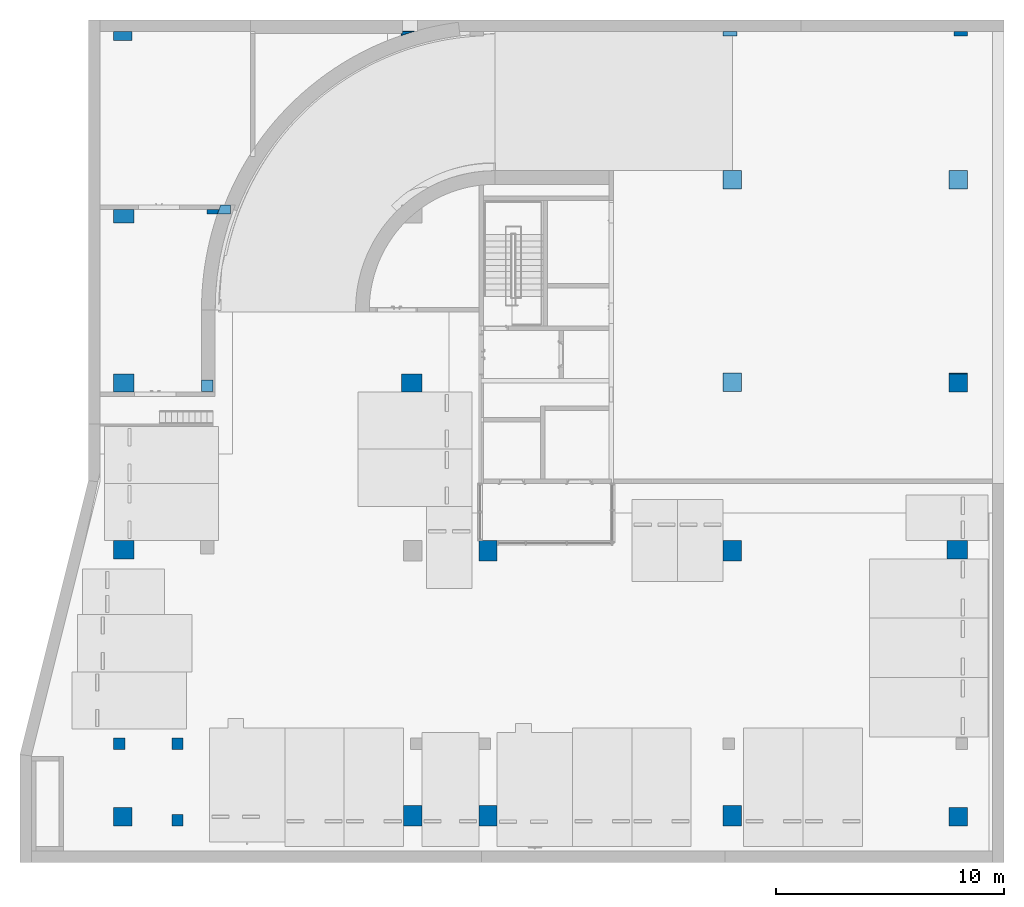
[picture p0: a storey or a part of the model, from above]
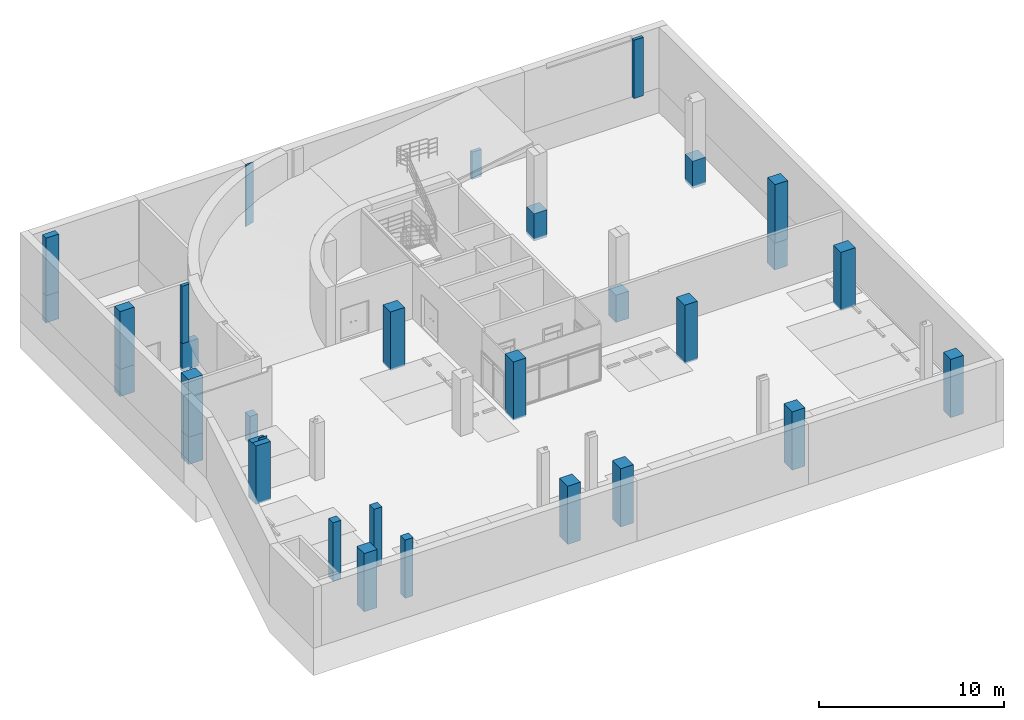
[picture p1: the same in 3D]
Properties of the parts of a building model (IFC2X3), part 1 of 39

# File
Description: ViewDefinition [CoordinationView_V2.0, QuantityTakeOffAddOnView]
File name: PJ - 001
Time: 2025-06-12T12:53:46+09:00
Written by: ODA SDAI 22.12
Made in: 23.0.11.19 - Exporter 23.0.11.19 - 대체 UI 23.0.11.19

# IfcProject, PJ - 001
LongName: 10S Sample Model; Phase: 기계-설계단계

# IfcSite, Default
RefLatitude: 37, 33, 59, 529418; RefLongitude: 126, 58, 40, 678710; RefElevation: 0 mm
ID 데이터 - 건물 이름: Sample Building
기타 - 대표용도코드: 140200; 연면적: 5000 m2; 카테고리: 프로젝트 정보; 클라이언트 이름: KBIMS; 프로젝트 발행 날짜: 2020.01.01; 프로젝트 번호: PJ - 001; 프로젝트 상태: 기계-설계단계; 프로젝트 이름: 10S Sample Model

# IfcBuilding, Sample Building
LongName: Sample Building
Pset_BuildingCommon - NumberOfStoreys: 13
ID 데이터 - 건물 이름: Sample Building
기타 - 카테고리: 프로젝트 정보; 대표용도코드: 140200; 연면적: 5000 m2; 클라이언트 이름: KBIMS; 프로젝트 발행 날짜: 2020.01.01; 프로젝트 번호: PJ - 001; 프로젝트 상태: 기계-설계단계; 프로젝트 이름: 10S Sample Model

# IfcBuildingStorey: 레벨:AN213-입단면도레벨 (13)
In: Sample Building
ID 데이터 - 구조: no
기타 - 유형: AN213-입단면도레벨; 유형 ID: 2825943; 카테고리: 레벨들; 패밀리: 레벨; 패밀리 및 유형: 레벨: AN213-입단면도레벨
ID 데이터(Type) - 유형 이름: AN213-입단면도레벨
구속조건(Type) - 높이 기준: 프로젝트 기준점
그래픽(Type) - 기호: AN213-입단면도레벨 : AN213-입단면도레벨 삼각헤드 GL+입면레벨; 끝 1 기본값 기호: yes; 끝 2 기본값 기호: no; 색상: 255; 선 두께: 1; 선 패턴: 중심선
기타(Type) - 카테고리: 레벨들; 패밀리 이름: 레벨
Name | LongName | Elevation (mm) | 건물 층 수 | 이름 | 입면도 (mm) | 계산 높이 (mm)
지하2층 | 지하2층 | -10100 | no | PIT | -11900 | 0
지하1층 | 지하1층 | -6100 | yes | 지하1층 | -6100 | 0
지상 1층 | 지상 1층 | 0 | yes | 지상 1층 | 0 | 1000 | 기타 - 기준지상층: yes; 피난층: yes
지상 2층 | 지상 2층 | 4800 | yes | 지상 2층 | 4800 | 1000
지상 3층 | 지상 3층 | 9300 | yes | 지상 3층 | 9300 | 1000
지상 4층 | 지상 4층 | 13400 | yes | 지상 4층 | 13400 | 1000
지상 5층 | 지상 5층 | 17500 | yes | 지상 5층 | 17500 | 1000
지상 6층 | 지상 6층 | 21600 | yes | 지상 6층 | 21600 | 1000
지상 7층 | 지상 7층 | 25700 | yes | 지상 7층 | 25700 | 1000
지상 8층 | 지상 8층 | 29800 | yes | 지상 8층 | 29800 | 1000
지상 9층 | 지상 9층 | 33900 | yes | 지상 9층 | 33900 | 1000
지상 10층 | 지상 10층 | 38400 | yes | 지상 10층 | 38400 | 1000
옥탑층 | 옥탑층 | 43400 | yes | 옥탑층 | 43400 | 0 | 기타 - 피난층: no

# IfcSpace: DA 103:6545426, 103
In: 지하2층
LongName: DA; InteriorOrExteriorSpace: INTERNAL
Pset_SpaceCommon - Reference: DA 103; FloorCovering: -; WallCovering: -; CeilingCovering: -
BaseQuantities - NetFloorArea: 3.78316 m2; Height: 2438.4 mm; GrossPerimeter: 9511.4 mm; GrossFloorArea: 3.78316 m2; GrossVolume: 9.22485 m3
ID 데이터 - 바닥 마감: -; 번호: 103; 베이스 마감: -; 벽 마감: -; 이름: DA; 천장 마감: -
공정 - 공정: 새 구성
구속조건 - 베이스 간격띄우기: 0 mm; 상한값: 지하2층; 한계 간격띄우기: 2438.4 mm; 레벨: 지하2층
기타 - 거실여부: no; 공정 ID: 0; 카테고리: 룸; 공간분류코드: 33416; 실ID: B218
에너지 해석 - 구역별 실제 전력 부하: 0; 구역별 실제 조명 부하: 0; 기초 전력 부하: 공간 유형별; 기초 조명 부하: 공간 유형별; 사람 수: 0; 열 부하 값: 공간 유형별; 전력 부하 단위: 전력 밀도; 조명 부하 단위: 전력 밀도; 1인당 잠열 취득: 58.6142 W; 1인당 현열 취득: 73.2678 W; 개인별 면적: 28.5714 m2; 실제 전력 부하: 0 W; 실제 조명 부하: 0 W; 지정된 구역별 전력 부하: 13.9931; 지정된 구역별 조명 부하: 10.7639; 지정된 전력 부하: 0 W; 지정된 조명 부하: 0 W; 천장속 조명 방사: 20; 총 개인별 열 취득: 131.882 W
치수 - 계산 높이: 0 mm; 무한한 높이: 2438.4 mm; 둘레: 9511.4 mm; 면적: 3.78316 m2; 체적: 9.22485 m3

# IfcSpace: DA 104:6545433, 104
In: 지하1층
LongName: DA; InteriorOrExteriorSpace: INTERNAL
Pset_SpaceCommon - Reference: DA 104; FloorCovering: -; WallCovering: -; CeilingCovering: -
BaseQuantities - NetFloorArea: 3.78316 m2; Height: 2438.4 mm; GrossPerimeter: 9511.4 mm; GrossFloorArea: 3.78316 m2; GrossVolume: 9.22485 m3
ID 데이터 - 바닥 마감: -; 번호: 104; 베이스 마감: -; 벽 마감: -; 이름: DA; 천장 마감: -
공정 - 공정: 새 구성
구속조건 - 베이스 간격띄우기: 0 mm; 상한값: 지하1층; 한계 간격띄우기: 2438.4 mm; 레벨: 지하1층
기타 - 거실여부: no; 공정 ID: 0; 카테고리: 룸; 공간분류코드: 33416; 실ID: B117
에너지 해석 - 구역별 실제 전력 부하: 0; 구역별 실제 조명 부하: 0; 기초 전력 부하: 공간 유형별; 기초 조명 부하: 공간 유형별; 사람 수: 0; 열 부하 값: 공간 유형별; 전력 부하 단위: 전력 밀도; 조명 부하 단위: 전력 밀도; 1인당 잠열 취득: 58.6142 W; 1인당 현열 취득: 73.2678 W; 개인별 면적: 28.5714 m2; 실제 전력 부하: 0 W; 실제 조명 부하: 0 W; 지정된 구역별 전력 부하: 13.9931; 지정된 구역별 조명 부하: 10.7639; 지정된 전력 부하: 0 W; 지정된 조명 부하: 0 W; 천장속 조명 방사: 20; 총 개인별 열 취득: 131.882 W
치수 - 계산 높이: 0 mm; 무한한 높이: 2438.4 mm; 둘레: 9511.4 mm; 면적: 3.78316 m2; 체적: 9.22485 m3

# IfcSpace: DA 12:5255727, 12
In: 지하2층
LongName: DA; InteriorOrExteriorSpace: INTERNAL
Pset_SpaceCommon - Reference: DA 12; FloorCovering: -; WallCovering: -; CeilingCovering: -
BaseQuantities - NetFloorArea: 2.74709 m2; Height: 4000 mm; GrossPerimeter: 11981.4 mm; GrossFloorArea: 2.74709 m2; GrossVolume: 10.9884 m3
ID 데이터 - 바닥 마감: -; 번호: 12; 베이스 마감: -; 벽 마감: -; 이름: DA; 천장 마감: -
공정 - 공정: 새 구성
구속조건 - 베이스 간격띄우기: 0 mm; 상한값: 지하2층; 레벨: 지하2층; 한계 간격띄우기: 4000 mm
기타 - 거실여부: no; 공정 ID: 0; 카테고리: 룸; 공간분류코드: 33416; 실ID: B216
에너지 해석 - 구역별 실제 전력 부하: 0; 구역별 실제 조명 부하: 0; 기초 전력 부하: 공간 유형별; 기초 조명 부하: 공간 유형별; 사람 수: 0; 열 부하 값: 공간 유형별; 전력 부하 단위: 전력 밀도; 조명 부하 단위: 전력 밀도; 1인당 잠열 취득: 58.6142 W; 1인당 현열 취득: 73.2678 W; 개인별 면적: 28.5714 m2; 실제 전력 부하: 0 W; 실제 조명 부하: 0 W; 지정된 구역별 전력 부하: 13.9931; 지정된 구역별 조명 부하: 10.7639; 지정된 전력 부하: 0 W; 지정된 조명 부하: 0 W; 천장속 조명 방사: 20; 총 개인별 열 취득: 131.882 W
치수 - 계산 높이: 0 mm; 둘레: 12013 mm; 면적: 2.74709 m2; 무한한 높이: 4000 mm; 체적: 10.9884 m3

# IfcSpace: DA 17:5255793, 17
In: 지하1층
LongName: DA; InteriorOrExteriorSpace: INTERNAL
Pset_SpaceCommon - Reference: DA 17; FloorCovering: -; WallCovering: -; CeilingCovering: -
BaseQuantities - NetFloorArea: 2.74709 m2; Height: 6100 mm; GrossFloorArea: 2.74709 m2; GrossVolume: 16.7572 m3
ID 데이터 - 바닥 마감: -; 번호: 17; 베이스 마감: -; 벽 마감: -; 이름: DA; 천장 마감: -
공정 - 공정: 새 구성
구속조건 - 베이스 간격띄우기: 0 mm; 상한값: 지하1층; 레벨: 지하1층; 한계 간격띄우기: 6100 mm
기타 - 거실여부: no; 공정 ID: 0; 카테고리: 룸; 공간분류코드: 33416; 실ID: B115
에너지 해석 - 구역별 실제 전력 부하: 0; 구역별 실제 조명 부하: 0; 기초 전력 부하: 공간 유형별; 기초 조명 부하: 공간 유형별; 사람 수: 0; 열 부하 값: 공간 유형별; 전력 부하 단위: 전력 밀도; 조명 부하 단위: 전력 밀도; 1인당 잠열 취득: 58.6142 W; 1인당 현열 취득: 73.2678 W; 개인별 면적: 28.5714 m2; 실제 전력 부하: 0 W; 실제 조명 부하: 0 W; 지정된 구역별 전력 부하: 13.9931; 지정된 구역별 조명 부하: 10.7639; 지정된 전력 부하: 0 W; 지정된 조명 부하: 0 W; 천장속 조명 방사: 20; 총 개인별 열 취득: 131.882 W
치수 - 계산 높이: 0 mm; 둘레: 12013 mm; 면적: 2.74709 m2; 무한한 높이: 6100 mm; 체적: 16.1379 m3

# IfcSpace: DA 24:5255899, 24
In: 지상 1층
LongName: DA; InteriorOrExteriorSpace: INTERNAL
Pset_SpaceCommon - Reference: DA 24; FloorCovering: -; WallCovering: -; CeilingCovering: -
BaseQuantities - NetFloorArea: 2.77393 m2; Height: 3000 mm; GrossPerimeter: 8897.14 mm; GrossFloorArea: 2.77393 m2; GrossVolume: 8.32178 m3
ID 데이터 - 바닥 마감: -; 번호: 24; 베이스 마감: -; 벽 마감: -; 이름: DA; 천장 마감: -
공정 - 공정: 새 구성
구속조건 - 베이스 간격띄우기: 0 mm; 상한값: 지상 1층; 레벨: 지상 1층; 한계 간격띄우기: 3000 mm
기타 - 거실여부: no; 공정 ID: 0; 카테고리: 룸; 공간분류코드: 33416; 실ID: 130
에너지 해석 - 구역별 실제 전력 부하: 0; 구역별 실제 조명 부하: 0; 기초 전력 부하: 공간 유형별; 기초 조명 부하: 공간 유형별; 사람 수: 0; 열 부하 값: 공간 유형별; 전력 부하 단위: 전력 밀도; 조명 부하 단위: 전력 밀도; 1인당 잠열 취득: 58.6142 W; 1인당 현열 취득: 73.2678 W; 개인별 면적: 28.5714 m2; 실제 전력 부하: 0 W; 실제 조명 부하: 0 W; 지정된 구역별 전력 부하: 13.9931; 지정된 구역별 조명 부하: 10.7639; 지정된 전력 부하: 0 W; 지정된 조명 부하: 0 W; 천장속 조명 방사: 20; 총 개인별 열 취득: 131.882 W
치수 - 계산 높이: 1000 mm; 둘레: 8897.14 mm; 면적: 2.77393 m2; 무한한 높이: 3000 mm; 체적: 8.32178 m3

# IfcSpace: DA 25:5255902, 25
In: 지상 1층
LongName: DA; InteriorOrExteriorSpace: INTERNAL
Pset_SpaceCommon - Reference: DA 25; FloorCovering: -; WallCovering: -; CeilingCovering: -
BaseQuantities - NetFloorArea: 3.78316 m2; Height: 3000 mm; GrossPerimeter: 9511.4 mm; GrossFloorArea: 3.78316 m2; GrossVolume: 11.3495 m3
ID 데이터 - 바닥 마감: -; 번호: 25; 베이스 마감: -; 벽 마감: -; 이름: DA; 천장 마감: -
공정 - 공정: 새 구성
구속조건 - 베이스 간격띄우기: 0 mm; 상한값: 지상 1층; 레벨: 지상 1층; 한계 간격띄우기: 3000 mm
기타 - 거실여부: no; 공정 ID: 0; 카테고리: 룸; 공간분류코드: 33416; 실ID: 131
에너지 해석 - 구역별 실제 전력 부하: 0; 구역별 실제 조명 부하: 0; 기초 전력 부하: 공간 유형별; 기초 조명 부하: 공간 유형별; 사람 수: 0; 열 부하 값: 공간 유형별; 전력 부하 단위: 전력 밀도; 조명 부하 단위: 전력 밀도; 1인당 잠열 취득: 58.6142 W; 1인당 현열 취득: 73.2678 W; 개인별 면적: 28.5714 m2; 실제 전력 부하: 0 W; 실제 조명 부하: 0 W; 지정된 구역별 전력 부하: 13.9931; 지정된 구역별 조명 부하: 10.7639; 지정된 전력 부하: 0 W; 지정된 조명 부하: 0 W; 천장속 조명 방사: 20; 총 개인별 열 취득: 131.882 W
치수 - 계산 높이: 1000 mm; 둘레: 9511.4 mm; 면적: 3.78316 m2; 무한한 높이: 3000 mm; 체적: 11.3495 m3

# IfcSpace: ROOF 324:4321595, 324
In: 옥탑층
LongName: ROOF; InteriorOrExteriorSpace: INTERNAL
Pset_SpaceCommon - Reference: ROOF 324; FloorCovering: 우레탄페인트; WallCovering: -; CeilingCovering: -
BaseQuantities - NetFloorArea: 1043.58 m2; Height: 4000 mm; GrossPerimeter: 188721 mm; GrossFloorArea: 1043.58 m2; GrossVolume: 4174.34 m3
ID 데이터 - 바닥 마감: 우레탄페인트; 번호: 324; 베이스 마감: -; 벽 마감: -; 이름: ROOF; 천장 마감: -
공정 - 공정: 새 구성
구속조건 - 베이스 간격띄우기: 0 mm; 레벨: 옥탑층; 상한값: 지붕층; 한계 간격띄우기: 0 mm
기타 - 공정 ID: 0; 카테고리: 룸; 공간분류코드: 33111; 실ID: RF07; 옥상광장여부: yes
에너지 해석 - 구역별 실제 전력 부하: 0; 구역별 실제 조명 부하: 0; 기초 전력 부하: 공간 유형별; 기초 조명 부하: 공간 유형별; 사람 수: 0; 열 부하 값: 공간 유형별; 전력 부하 단위: 전력 밀도; 조명 부하 단위: 전력 밀도; 1인당 잠열 취득: 58.6142 W; 1인당 현열 취득: 73.2678 W; 개인별 면적: 28.5714 m2; 실제 전력 부하: 0 W; 실제 조명 부하: 0 W; 지정된 구역별 전력 부하: 13.9931; 지정된 구역별 조명 부하: 10.7639; 지정된 전력 부하: 0 W; 지정된 조명 부하: 0 W; 천장속 조명 방사: 20; 총 개인별 열 취득: 131.882 W
치수 - 계산 높이: 0 mm; 둘레: 188721 mm; 면적: 1043.58 m2; 무한한 높이: 4000 mm; 체적: 4174.34 m3

# IfcSpace: 건축면적 4:3581452, 4
In: 지상 2층
LongName: 건축면적; InteriorOrExteriorSpace: INTERNAL; Group: 건축 면적
Pset_SpaceCommon - Reference: 건축면적 4
BaseQuantities - NetFloorArea: 1167.11 m2; Height: 4500 mm; GrossFloorArea: 1167.11 m2; GrossVolume: 5252.02 m3
ID 데이터 - 번호: 4; 이름: 건축면적; 해설: BIM 산출
구속조건 - 레벨: 지상 2층
기타 - 카테고리: 면적; 면적 양식 ID: 9490; 면적 유형: 건축 면적
치수 - 계산 높이: 1000 mm; 둘레: 147400 mm; 면적: 1167.11 m2

# IfcSpace: 계단실1 132:3690442, 132
In: 지하2층
LongName: 계단실1; InteriorOrExteriorSpace: INTERNAL
Pset_SpaceCommon - Reference: 계단실1 132; FloorCovering: T30 화강석 물갈기; WallCovering: -; CeilingCovering: 무늬코트뿜칠
BaseQuantities - NetFloorArea: 14.3102 m2; Height: 4000 mm; GrossPerimeter: 16203.7 mm; GrossFloorArea: 14.3102 m2; GrossVolume: 57.2406 m3
ID 데이터 - 바닥 마감: T30 화강석 물갈기; 번호: 132; 베이스 마감: 목재 걸레받이; 벽 마감: -; 이름: 계단실1; 천장 마감: 무늬코트뿜칠
공정 - 공정: 새 구성
구속조건 - 베이스 간격띄우기: 0 mm; 상한값: 지하2층; 레벨: 지하2층; 한계 간격띄우기: 4000 mm
기타 - 거실여부: no; 공정 ID: 0; 카테고리: 룸; 공간분류코드: 33101; 실ID: B208
에너지 해석 - 구역별 실제 전력 부하: 0; 구역별 실제 조명 부하: 0; 기초 전력 부하: 공간 유형별; 기초 조명 부하: 공간 유형별; 사람 수: 0; 열 부하 값: 공간 유형별; 전력 부하 단위: 전력 밀도; 조명 부하 단위: 전력 밀도; 1인당 잠열 취득: 58.6142 W; 1인당 현열 취득: 73.2678 W; 개인별 면적: 28.5714 m2; 실제 전력 부하: 0 W; 실제 조명 부하: 0 W; 지정된 구역별 전력 부하: 13.9931; 지정된 구역별 조명 부하: 10.7639; 지정된 전력 부하: 0 W; 지정된 조명 부하: 0 W; 천장속 조명 방사: 20; 총 개인별 열 취득: 131.882 W
치수 - 계산 높이: 0 mm; 둘레: 16203.7 mm; 면적: 14.3102 m2; 무한한 높이: 4000 mm; 체적: 57.2406 m3

# IfcSpace: 계단실1 139:3691074, 139
In: 지하1층
LongName: 계단실1; InteriorOrExteriorSpace: INTERNAL
Pset_SpaceCommon - Reference: 계단실1 139; FloorCovering: T30 화강석 물갈기; WallCovering: -; CeilingCovering: 무늬코트뿜칠
BaseQuantities - NetFloorArea: 14.0097 m2; Height: 6100 mm; GrossPerimeter: 16056 mm; GrossFloorArea: 14.0097 m2; GrossVolume: 85.4594 m3
ID 데이터 - 바닥 마감: T30 화강석 물갈기; 번호: 139; 베이스 마감: 목재 걸레받이; 벽 마감: -; 이름: 계단실1; 천장 마감: 무늬코트뿜칠
공정 - 공정: 새 구성
구속조건 - 베이스 간격띄우기: 0 mm; 상한값: 지하1층; 레벨: 지하1층; 한계 간격띄우기: 6100 mm
기타 - 거실여부: no; 공정 ID: 0; 카테고리: 룸; 공간분류코드: 33101; 실ID: B103
에너지 해석 - 구역별 실제 전력 부하: 0; 구역별 실제 조명 부하: 0; 기초 전력 부하: 공간 유형별; 기초 조명 부하: 공간 유형별; 사람 수: 0; 열 부하 값: 공간 유형별; 전력 부하 단위: 전력 밀도; 조명 부하 단위: 전력 밀도; 1인당 잠열 취득: 58.6142 W; 1인당 현열 취득: 73.2678 W; 개인별 면적: 28.5714 m2; 실제 전력 부하: 0 W; 실제 조명 부하: 0 W; 지정된 구역별 전력 부하: 13.9931; 지정된 구역별 조명 부하: 10.7639; 지정된 전력 부하: 0 W; 지정된 조명 부하: 0 W; 천장속 조명 방사: 20; 총 개인별 열 취득: 131.882 W
치수 - 계산 높이: 0 mm; 둘레: 17220 mm; 면적: 14.0097 m2; 무한한 높이: 6100 mm; 체적: 85.4594 m3

# IfcSpace: 계단실1 164:3691256, 164
In: 지상 1층
LongName: 계단실1; InteriorOrExteriorSpace: INTERNAL
Pset_SpaceCommon - Reference: 계단실1 164; FloorCovering: T30 화강석 물갈기; WallCovering: -; CeilingCovering: 무늬코트뿜칠
BaseQuantities - NetFloorArea: 14.0097 m2; Height: 4950 mm; GrossPerimeter: 16056 mm; GrossFloorArea: 14.0097 m2; GrossVolume: 69.3482 m3
ID 데이터 - 바닥 마감: T30 화강석 물갈기; 번호: 164; 베이스 마감: 목재 걸레받이; 벽 마감: -; 이름: 계단실1; 천장 마감: 무늬코트뿜칠
공정 - 공정: 새 구성
구속조건 - 상한값: 지상 1층; 레벨: 지상 1층; 베이스 간격띄우기: -150 mm; 한계 간격띄우기: 4800 mm
기타 - 거실여부: no; 공정 ID: 0; 카테고리: 룸; 방화구획: yes; 공간분류코드: 33101; 실ID: 116
에너지 해석 - 구역별 실제 전력 부하: 0; 구역별 실제 조명 부하: 0; 기초 전력 부하: 공간 유형별; 기초 조명 부하: 공간 유형별; 사람 수: 0; 열 부하 값: 공간 유형별; 전력 부하 단위: 전력 밀도; 조명 부하 단위: 전력 밀도; 1인당 잠열 취득: 58.6142 W; 1인당 현열 취득: 73.2678 W; 개인별 면적: 28.5714 m2; 실제 전력 부하: 0 W; 실제 조명 부하: 0 W; 지정된 구역별 전력 부하: 13.9931; 지정된 구역별 조명 부하: 10.7639; 지정된 전력 부하: 0 W; 지정된 조명 부하: 0 W; 천장속 조명 방사: 20; 총 개인별 열 취득: 131.882 W
치수 - 계산 높이: 1000 mm; 둘레: 16056 mm; 면적: 14.0097 m2; 무한한 높이: 4950 mm; 체적: 69.3482 m3

# IfcSpace: 계단실1 186:3691546, 186
In: 지상 2층
LongName: 계단실1; InteriorOrExteriorSpace: INTERNAL
Pset_SpaceCommon - Reference: 계단실1 186; FloorCovering: T30 화강석 물갈기; WallCovering: -; CeilingCovering: 무늬코트뿜칠
BaseQuantities - NetFloorArea: 14.0097 m2; Height: 4500 mm; GrossPerimeter: 16056 mm; GrossFloorArea: 14.0097 m2; GrossVolume: 63.0438 m3
ID 데이터 - 바닥 마감: T30 화강석 물갈기; 번호: 186; 베이스 마감: 목재 걸레받이; 벽 마감: -; 이름: 계단실1; 천장 마감: 무늬코트뿜칠
공정 - 공정: 새 구성
구속조건 - 베이스 간격띄우기: 0 mm; 상한값: 지상 2층; 레벨: 지상 2층; 한계 간격띄우기: 4500 mm
기타 - 거실여부: no; 공정 ID: 0; 카테고리: 룸; 방화구획: yes; 공간분류코드: 33101; 실ID: 208
에너지 해석 - 구역별 실제 전력 부하: 0; 구역별 실제 조명 부하: 0; 기초 전력 부하: 공간 유형별; 기초 조명 부하: 공간 유형별; 사람 수: 0; 열 부하 값: 공간 유형별; 전력 부하 단위: 전력 밀도; 조명 부하 단위: 전력 밀도; 1인당 잠열 취득: 58.6142 W; 1인당 현열 취득: 73.2678 W; 개인별 면적: 28.5714 m2; 실제 전력 부하: 0 W; 실제 조명 부하: 0 W; 지정된 구역별 전력 부하: 13.9931; 지정된 구역별 조명 부하: 10.7639; 지정된 전력 부하: 0 W; 지정된 조명 부하: 0 W; 천장속 조명 방사: 20; 총 개인별 열 취득: 131.882 W
치수 - 계산 높이: 1000 mm; 둘레: 16056 mm; 면적: 14.0097 m2; 무한한 높이: 4500 mm; 체적: 63.0438 m3

# IfcSpace: 계단실1 199:3691774, 199
In: 지상 3층
LongName: 계단실1; InteriorOrExteriorSpace: INTERNAL
Pset_SpaceCommon - Reference: 계단실1 199; FloorCovering: T30 화강석 물갈기; WallCovering: -; CeilingCovering: 무늬코트뿜칠
BaseQuantities - NetFloorArea: 14.0112 m2; Height: 4100 mm; GrossPerimeter: 16056.5 mm; GrossFloorArea: 14.0112 m2; GrossVolume: 57.4458 m3
ID 데이터 - 바닥 마감: T30 화강석 물갈기; 번호: 199; 베이스 마감: 목재 걸레받이; 벽 마감: -; 이름: 계단실1; 천장 마감: 무늬코트뿜칠
공정 - 공정: 새 구성
구속조건 - 베이스 간격띄우기: 0 mm; 상한값: 지상 3층; 레벨: 지상 3층; 한계 간격띄우기: 4100 mm
기타 - 거실여부: no; 공정 ID: 0; 카테고리: 룸; 방화구획: yes; 공간분류코드: 33101; 실ID: 308
에너지 해석 - 구역별 실제 전력 부하: 0; 구역별 실제 조명 부하: 0; 기초 전력 부하: 공간 유형별; 기초 조명 부하: 공간 유형별; 사람 수: 0; 열 부하 값: 공간 유형별; 전력 부하 단위: 전력 밀도; 조명 부하 단위: 전력 밀도; 1인당 잠열 취득: 58.6142 W; 1인당 현열 취득: 73.2678 W; 개인별 면적: 28.5714 m2; 실제 전력 부하: 0 W; 실제 조명 부하: 0 W; 지정된 구역별 전력 부하: 13.9931; 지정된 구역별 조명 부하: 10.7639; 지정된 전력 부하: 0 W; 지정된 조명 부하: 0 W; 천장속 조명 방사: 20; 총 개인별 열 취득: 131.882 W
치수 - 계산 높이: 1000 mm; 둘레: 16056.5 mm; 면적: 14.0112 m2; 무한한 높이: 4100 mm; 체적: 57.4458 m3

# IfcSpace: 계단실1 219:3692888, 219
In: 지상 4층
LongName: 계단실1; InteriorOrExteriorSpace: INTERNAL
Pset_SpaceCommon - Reference: 계단실1 219; FloorCovering: T30 화강석 물갈기; WallCovering: -; CeilingCovering: 무늬코트뿜칠
BaseQuantities - NetFloorArea: 14.0097 m2; Height: 4100 mm; GrossPerimeter: 16056 mm; GrossFloorArea: 14.0097 m2; GrossVolume: 57.4399 m3
ID 데이터 - 바닥 마감: T30 화강석 물갈기; 번호: 219; 베이스 마감: 목재 걸레받이; 벽 마감: -; 이름: 계단실1; 천장 마감: 무늬코트뿜칠
공정 - 공정: 새 구성
구속조건 - 베이스 간격띄우기: 0 mm; 상한값: 지상 4층; 레벨: 지상 4층; 한계 간격띄우기: 4100 mm
기타 - 거실여부: no; 공정 ID: 0; 카테고리: 룸; 방화구획: yes; 공간분류코드: 33101; 실ID: 408
에너지 해석 - 구역별 실제 전력 부하: 0; 구역별 실제 조명 부하: 0; 기초 전력 부하: 공간 유형별; 기초 조명 부하: 공간 유형별; 사람 수: 0; 열 부하 값: 공간 유형별; 전력 부하 단위: 전력 밀도; 조명 부하 단위: 전력 밀도; 1인당 잠열 취득: 58.6142 W; 1인당 현열 취득: 73.2678 W; 개인별 면적: 28.5714 m2; 실제 전력 부하: 0 W; 실제 조명 부하: 0 W; 지정된 구역별 전력 부하: 13.9931; 지정된 구역별 조명 부하: 10.7639; 지정된 전력 부하: 0 W; 지정된 조명 부하: 0 W; 천장속 조명 방사: 20; 총 개인별 열 취득: 131.882 W
치수 - 계산 높이: 1000 mm; 둘레: 16056 mm; 면적: 14.0097 m2; 무한한 높이: 4100 mm; 체적: 57.4399 m3

# IfcSpace: 계단실1 234:3692955, 234
In: 지상 5층
LongName: 계단실1; InteriorOrExteriorSpace: INTERNAL
Pset_SpaceCommon - Reference: 계단실1 234; FloorCovering: T30 화강석 물갈기; WallCovering: -; CeilingCovering: 무늬코트뿜칠
BaseQuantities - NetFloorArea: 14.0097 m2; Height: 4100 mm; GrossPerimeter: 16056 mm; GrossFloorArea: 14.0097 m2; GrossVolume: 57.4399 m3
ID 데이터 - 바닥 마감: T30 화강석 물갈기; 번호: 234; 베이스 마감: 목재 걸레받이; 벽 마감: -; 이름: 계단실1; 천장 마감: 무늬코트뿜칠
공정 - 공정: 새 구성
구속조건 - 베이스 간격띄우기: 0 mm; 상한값: 지상 5층; 레벨: 지상 5층; 한계 간격띄우기: 4100 mm
기타 - 거실여부: no; 공정 ID: 0; 카테고리: 룸; 방화구획: yes; 공간분류코드: 33101; 실ID: 511
에너지 해석 - 구역별 실제 전력 부하: 0; 구역별 실제 조명 부하: 0; 기초 전력 부하: 공간 유형별; 기초 조명 부하: 공간 유형별; 사람 수: 0; 열 부하 값: 공간 유형별; 전력 부하 단위: 전력 밀도; 조명 부하 단위: 전력 밀도; 1인당 잠열 취득: 58.6142 W; 1인당 현열 취득: 73.2678 W; 개인별 면적: 28.5714 m2; 실제 전력 부하: 0 W; 실제 조명 부하: 0 W; 지정된 구역별 전력 부하: 13.9931; 지정된 구역별 조명 부하: 10.7639; 지정된 전력 부하: 0 W; 지정된 조명 부하: 0 W; 천장속 조명 방사: 20; 총 개인별 열 취득: 131.882 W
치수 - 계산 높이: 1000 mm; 둘레: 16056 mm; 면적: 14.0097 m2; 무한한 높이: 4100 mm; 체적: 57.4399 m3

# IfcSpace: 계단실1 249:3694141, 249
In: 지상 6층
LongName: 계단실1; InteriorOrExteriorSpace: INTERNAL
Pset_SpaceCommon - Reference: 계단실1 249; FloorCovering: T30 화강석 물갈기; WallCovering: -; CeilingCovering: 무늬코트뿜칠
BaseQuantities - NetFloorArea: 14.0097 m2; Height: 4100 mm; GrossPerimeter: 16056 mm; GrossFloorArea: 14.0097 m2; GrossVolume: 57.4399 m3
ID 데이터 - 바닥 마감: T30 화강석 물갈기; 번호: 249; 베이스 마감: 목재 걸레받이; 벽 마감: -; 이름: 계단실1; 천장 마감: 무늬코트뿜칠
공정 - 공정: 새 구성
구속조건 - 베이스 간격띄우기: 0 mm; 상한값: 지상 6층; 레벨: 지상 6층; 한계 간격띄우기: 4100 mm
기타 - 거실여부: no; 공정 ID: 0; 카테고리: 룸; 방화구획: yes; 공간분류코드: 33101; 실ID: 611
에너지 해석 - 구역별 실제 전력 부하: 0; 구역별 실제 조명 부하: 0; 기초 전력 부하: 공간 유형별; 기초 조명 부하: 공간 유형별; 사람 수: 0; 열 부하 값: 공간 유형별; 전력 부하 단위: 전력 밀도; 조명 부하 단위: 전력 밀도; 1인당 잠열 취득: 58.6142 W; 1인당 현열 취득: 73.2678 W; 개인별 면적: 28.5714 m2; 실제 전력 부하: 0 W; 실제 조명 부하: 0 W; 지정된 구역별 전력 부하: 13.9931; 지정된 구역별 조명 부하: 10.7639; 지정된 전력 부하: 0 W; 지정된 조명 부하: 0 W; 천장속 조명 방사: 20; 총 개인별 열 취득: 131.882 W
치수 - 계산 높이: 1000 mm; 둘레: 16056 mm; 면적: 14.0097 m2; 무한한 높이: 4100 mm; 체적: 57.4399 m3

# IfcSpace: 계단실1 263:3694343, 263
In: 지상 7층
LongName: 계단실1; InteriorOrExteriorSpace: INTERNAL
Pset_SpaceCommon - Reference: 계단실1 263; FloorCovering: T30 화강석 물갈기; WallCovering: -; CeilingCovering: 무늬코트뿜칠
BaseQuantities - NetFloorArea: 14.0097 m2; Height: 4100 mm; GrossPerimeter: 16056 mm; GrossFloorArea: 14.0097 m2; GrossVolume: 57.4399 m3
ID 데이터 - 바닥 마감: T30 화강석 물갈기; 번호: 263; 베이스 마감: 목재 걸레받이; 벽 마감: -; 이름: 계단실1; 천장 마감: 무늬코트뿜칠
공정 - 공정: 새 구성
구속조건 - 베이스 간격띄우기: 0 mm; 상한값: 지상 7층; 레벨: 지상 7층; 한계 간격띄우기: 4100 mm
기타 - 거실여부: no; 공정 ID: 0; 카테고리: 룸; 방화구획: yes; 공간분류코드: 33101; 실ID: 708
에너지 해석 - 구역별 실제 전력 부하: 0; 구역별 실제 조명 부하: 0; 기초 전력 부하: 공간 유형별; 기초 조명 부하: 공간 유형별; 사람 수: 0; 열 부하 값: 공간 유형별; 전력 부하 단위: 전력 밀도; 조명 부하 단위: 전력 밀도; 1인당 잠열 취득: 58.6142 W; 1인당 현열 취득: 73.2678 W; 개인별 면적: 28.5714 m2; 실제 전력 부하: 0 W; 실제 조명 부하: 0 W; 지정된 구역별 전력 부하: 13.9931; 지정된 구역별 조명 부하: 10.7639; 지정된 전력 부하: 0 W; 지정된 조명 부하: 0 W; 천장속 조명 방사: 20; 총 개인별 열 취득: 131.882 W
치수 - 계산 높이: 1000 mm; 둘레: 16056 mm; 면적: 14.0097 m2; 무한한 높이: 4100 mm; 체적: 57.4399 m3

# IfcSpace: 계단실1 281:3694575, 281
In: 지상 8층
LongName: 계단실1; InteriorOrExteriorSpace: INTERNAL
Pset_SpaceCommon - Reference: 계단실1 281; FloorCovering: T30 화강석 물갈기; WallCovering: -; CeilingCovering: 무늬코트뿜칠
BaseQuantities - NetFloorArea: 14.0097 m2; Height: 4100 mm; GrossPerimeter: 16056 mm; GrossFloorArea: 14.0097 m2; GrossVolume: 57.4399 m3
ID 데이터 - 바닥 마감: T30 화강석 물갈기; 번호: 281; 베이스 마감: 목재 걸레받이; 벽 마감: -; 이름: 계단실1; 천장 마감: 무늬코트뿜칠
공정 - 공정: 새 구성
구속조건 - 베이스 간격띄우기: 0 mm; 상한값: 지상 8층; 레벨: 지상 8층; 한계 간격띄우기: 4100 mm
기타 - 거실여부: no; 공정 ID: 0; 카테고리: 룸; 공간분류코드: 33101; 실ID: 808
에너지 해석 - 구역별 실제 전력 부하: 0; 구역별 실제 조명 부하: 0; 기초 전력 부하: 공간 유형별; 기초 조명 부하: 공간 유형별; 사람 수: 0; 열 부하 값: 공간 유형별; 전력 부하 단위: 전력 밀도; 조명 부하 단위: 전력 밀도; 1인당 잠열 취득: 58.6142 W; 1인당 현열 취득: 73.2678 W; 개인별 면적: 28.5714 m2; 실제 전력 부하: 0 W; 실제 조명 부하: 0 W; 지정된 구역별 전력 부하: 13.9931; 지정된 구역별 조명 부하: 10.7639; 지정된 전력 부하: 0 W; 지정된 조명 부하: 0 W; 천장속 조명 방사: 20; 총 개인별 열 취득: 131.882 W
치수 - 계산 높이: 1000 mm; 둘레: 16056 mm; 면적: 14.0097 m2; 무한한 높이: 4100 mm; 체적: 57.4399 m3

# IfcSpace: 계단실1 296:3694750, 296
In: 지상 9층
LongName: 계단실1; InteriorOrExteriorSpace: INTERNAL
Pset_SpaceCommon - Reference: 계단실1 296; FloorCovering: T30 화강석 물갈기; WallCovering: -; CeilingCovering: 무늬코트뿜칠
BaseQuantities - NetFloorArea: 14.0132 m2; Height: 4500 mm; GrossPerimeter: 16057.3 mm; GrossFloorArea: 14.0132 m2; GrossVolume: 63.0594 m3
ID 데이터 - 바닥 마감: T30 화강석 물갈기; 번호: 296; 베이스 마감: 목재 걸레받이; 벽 마감: -; 이름: 계단실1; 천장 마감: 무늬코트뿜칠
공정 - 공정: 새 구성
구속조건 - 베이스 간격띄우기: 0 mm; 상한값: 지상 9층; 레벨: 지상 9층; 한계 간격띄우기: 4500 mm
기타 - 거실여부: no; 공정 ID: 0; 카테고리: 룸; 공간분류코드: 33101; 실ID: 907
에너지 해석 - 구역별 실제 전력 부하: 0; 구역별 실제 조명 부하: 0; 기초 전력 부하: 공간 유형별; 기초 조명 부하: 공간 유형별; 사람 수: 0; 열 부하 값: 공간 유형별; 전력 부하 단위: 전력 밀도; 조명 부하 단위: 전력 밀도; 1인당 잠열 취득: 58.6142 W; 1인당 현열 취득: 73.2678 W; 개인별 면적: 28.5714 m2; 실제 전력 부하: 0 W; 실제 조명 부하: 0 W; 지정된 구역별 전력 부하: 13.9931; 지정된 구역별 조명 부하: 10.7639; 지정된 전력 부하: 0 W; 지정된 조명 부하: 0 W; 천장속 조명 방사: 20; 총 개인별 열 취득: 131.882 W
치수 - 계산 높이: 1000 mm; 둘레: 16057.3 mm; 면적: 14.0132 m2; 무한한 높이: 4500 mm; 체적: 63.0594 m3

# IfcSpace: 계단실1 309:3694922, 309
In: 지상 10층
LongName: 계단실1; InteriorOrExteriorSpace: INTERNAL
Pset_SpaceCommon - Reference: 계단실1 309; FloorCovering: T30 화강석 물갈기; WallCovering: -; CeilingCovering: 무늬코트뿜칠
BaseQuantities - NetFloorArea: 13.9934 m2; Height: 5000 mm; GrossPerimeter: 16050 mm; GrossFloorArea: 13.9934 m2; GrossVolume: 69.9668 m3
ID 데이터 - 바닥 마감: T30 화강석 물갈기; 번호: 309; 베이스 마감: 목재 걸레받이; 벽 마감: -; 이름: 계단실1; 천장 마감: 무늬코트뿜칠
공정 - 공정: 새 구성
구속조건 - 베이스 간격띄우기: 0 mm; 상한값: 지상 10층; 레벨: 지상 10층; 한계 간격띄우기: 5000 mm
기타 - 거실여부: no; 공정 ID: 0; 카테고리: 룸; 공간분류코드: 33101; 실ID: 1005
에너지 해석 - 구역별 실제 전력 부하: 0; 구역별 실제 조명 부하: 0; 기초 전력 부하: 공간 유형별; 기초 조명 부하: 공간 유형별; 사람 수: 0; 열 부하 값: 공간 유형별; 전력 부하 단위: 전력 밀도; 조명 부하 단위: 전력 밀도; 1인당 잠열 취득: 58.6142 W; 1인당 현열 취득: 73.2678 W; 개인별 면적: 28.5714 m2; 실제 전력 부하: 0 W; 실제 조명 부하: 0 W; 지정된 구역별 전력 부하: 13.9931; 지정된 구역별 조명 부하: 10.7639; 지정된 전력 부하: 0 W; 지정된 조명 부하: 0 W; 천장속 조명 방사: 20; 총 개인별 열 취득: 131.882 W
치수 - 계산 높이: 1000 mm; 둘레: 16050 mm; 면적: 13.9934 m2; 무한한 높이: 5000 mm; 체적: 69.9668 m3

# IfcSpace: 계단실1 319:3695655, 319
In: 옥탑층
LongName: 계단실1; InteriorOrExteriorSpace: INTERNAL
Pset_SpaceCommon - Reference: 계단실1 319; FloorCovering: T30 화강석 물갈기; WallCovering: -; CeilingCovering: 무늬코트뿜칠
BaseQuantities - NetFloorArea: 14.1147 m2; Height: 3850 mm; GrossFloorArea: 14.1147 m2; GrossVolume: 54.3415 m3
ID 데이터 - 바닥 마감: T30 화강석 물갈기; 번호: 319; 베이스 마감: 목재 걸레받이; 벽 마감: -; 이름: 계단실1; 천장 마감: 무늬코트뿜칠
공정 - 공정: 새 구성
구속조건 - 베이스 간격띄우기: 0 mm; 상한값: 옥탑층; 레벨: 옥탑층; 한계 간격띄우기: 3850 mm
기타 - 거실여부: no; 공정 ID: 0; 카테고리: 룸; 공간분류코드: 33101; 실ID: RF02
에너지 해석 - 구역별 실제 전력 부하: 0; 구역별 실제 조명 부하: 0; 기초 전력 부하: 공간 유형별; 기초 조명 부하: 공간 유형별; 사람 수: 0; 열 부하 값: 공간 유형별; 전력 부하 단위: 전력 밀도; 조명 부하 단위: 전력 밀도; 1인당 잠열 취득: 58.6142 W; 1인당 현열 취득: 73.2678 W; 개인별 면적: 28.5714 m2; 실제 전력 부하: 0 W; 실제 조명 부하: 0 W; 지정된 구역별 전력 부하: 13.9931; 지정된 구역별 조명 부하: 10.7639; 지정된 전력 부하: 0 W; 지정된 조명 부하: 0 W; 천장속 조명 방사: 20; 총 개인별 열 취득: 131.882 W
치수 - 계산 높이: 0 mm; 둘레: 16094.4 mm; 면적: 14.1147 m2; 무한한 높이: 3850 mm; 체적: 42.355 m3

# IfcSpace: 계단실2 165:3691259, 165
In: 지상 1층
LongName: 계단실2; InteriorOrExteriorSpace: INTERNAL
Pset_SpaceCommon - Reference: 계단실2 165; FloorCovering: T30 화강석 물갈기; WallCovering: -; CeilingCovering: 무늬코트뿜칠
BaseQuantities - NetFloorArea: 14.0097 m2; Height: 4800 mm; GrossPerimeter: 16056 mm; GrossFloorArea: 14.0097 m2; GrossVolume: 67.2468 m3
ID 데이터 - 바닥 마감: T30 화강석 물갈기; 번호: 165; 베이스 마감: 목재 걸레받이; 벽 마감: -; 이름: 계단실2; 천장 마감: 무늬코트뿜칠
공정 - 공정: 새 구성
구속조건 - 베이스 간격띄우기: 0 mm; 상한값: 지상 1층; 레벨: 지상 1층; 한계 간격띄우기: 4800 mm
기타 - 거실여부: no; 공정 ID: 0; 카테고리: 룸; 방화구획: yes; 공간분류코드: 33101; 실ID: 117
에너지 해석 - 구역별 실제 전력 부하: 0; 구역별 실제 조명 부하: 0; 기초 전력 부하: 공간 유형별; 기초 조명 부하: 공간 유형별; 사람 수: 0; 열 부하 값: 공간 유형별; 전력 부하 단위: 전력 밀도; 조명 부하 단위: 전력 밀도; 1인당 잠열 취득: 58.6142 W; 1인당 현열 취득: 73.2678 W; 개인별 면적: 28.5714 m2; 실제 전력 부하: 0 W; 실제 조명 부하: 0 W; 지정된 구역별 전력 부하: 13.9931; 지정된 구역별 조명 부하: 10.7639; 지정된 전력 부하: 0 W; 지정된 조명 부하: 0 W; 천장속 조명 방사: 20; 총 개인별 열 취득: 131.882 W
치수 - 계산 높이: 1000 mm; 둘레: 16056 mm; 면적: 14.0097 m2; 무한한 높이: 4800 mm; 체적: 67.2468 m3

# IfcSpace: 계단실2 187:3691549, 187
In: 지상 2층
LongName: 계단실2; InteriorOrExteriorSpace: INTERNAL
Pset_SpaceCommon - Reference: 계단실2 187; FloorCovering: T30 화강석 물갈기; WallCovering: -; CeilingCovering: 무늬코트뿜칠
BaseQuantities - NetFloorArea: 14.0097 m2; Height: 4500 mm; GrossPerimeter: 16056 mm; GrossFloorArea: 14.0097 m2; GrossVolume: 63.0438 m3
ID 데이터 - 바닥 마감: T30 화강석 물갈기; 번호: 187; 베이스 마감: 목재 걸레받이; 벽 마감: -; 이름: 계단실2; 천장 마감: 무늬코트뿜칠
공정 - 공정: 새 구성
구속조건 - 베이스 간격띄우기: 0 mm; 상한값: 지상 2층; 레벨: 지상 2층; 한계 간격띄우기: 4500 mm
기타 - 거실여부: no; 공정 ID: 0; 카테고리: 룸; 방화구획: yes; 공간분류코드: 33101; 실ID: 209
에너지 해석 - 구역별 실제 전력 부하: 0; 구역별 실제 조명 부하: 0; 기초 전력 부하: 공간 유형별; 기초 조명 부하: 공간 유형별; 사람 수: 0; 열 부하 값: 공간 유형별; 전력 부하 단위: 전력 밀도; 조명 부하 단위: 전력 밀도; 1인당 잠열 취득: 58.6142 W; 1인당 현열 취득: 73.2678 W; 개인별 면적: 28.5714 m2; 실제 전력 부하: 0 W; 실제 조명 부하: 0 W; 지정된 구역별 전력 부하: 13.9931; 지정된 구역별 조명 부하: 10.7639; 지정된 전력 부하: 0 W; 지정된 조명 부하: 0 W; 천장속 조명 방사: 20; 총 개인별 열 취득: 131.882 W
치수 - 계산 높이: 1000 mm; 둘레: 16056 mm; 면적: 14.0097 m2; 무한한 높이: 4500 mm; 체적: 63.0438 m3

# IfcSpace: 계단실2 200:3691777, 200
In: 지상 3층
LongName: 계단실2; InteriorOrExteriorSpace: INTERNAL
Pset_SpaceCommon - Reference: 계단실2 200; FloorCovering: T30 화강석 물갈기; WallCovering: -; CeilingCovering: 무늬코트뿜칠
BaseQuantities - NetFloorArea: 14.0097 m2; Height: 4100 mm; GrossPerimeter: 16056 mm; GrossFloorArea: 14.0097 m2; GrossVolume: 57.4399 m3
ID 데이터 - 바닥 마감: T30 화강석 물갈기; 번호: 200; 베이스 마감: 목재 걸레받이; 벽 마감: -; 이름: 계단실2; 천장 마감: 무늬코트뿜칠
공정 - 공정: 새 구성
구속조건 - 베이스 간격띄우기: 0 mm; 상한값: 지상 3층; 레벨: 지상 3층; 한계 간격띄우기: 4100 mm
기타 - 거실여부: no; 공정 ID: 0; 카테고리: 룸; 방화구획: yes; 공간분류코드: 33101; 실ID: 309
에너지 해석 - 구역별 실제 전력 부하: 0; 구역별 실제 조명 부하: 0; 기초 전력 부하: 공간 유형별; 기초 조명 부하: 공간 유형별; 사람 수: 0; 열 부하 값: 공간 유형별; 전력 부하 단위: 전력 밀도; 조명 부하 단위: 전력 밀도; 1인당 잠열 취득: 58.6142 W; 1인당 현열 취득: 73.2678 W; 개인별 면적: 28.5714 m2; 실제 전력 부하: 0 W; 실제 조명 부하: 0 W; 지정된 구역별 전력 부하: 13.9931; 지정된 구역별 조명 부하: 10.7639; 지정된 전력 부하: 0 W; 지정된 조명 부하: 0 W; 천장속 조명 방사: 20; 총 개인별 열 취득: 131.882 W
치수 - 계산 높이: 1000 mm; 둘레: 16056 mm; 면적: 14.0097 m2; 무한한 높이: 4100 mm; 체적: 57.4399 m3

# IfcSpace: 계단실2 220:3692891, 220
In: 지상 4층
LongName: 계단실2; InteriorOrExteriorSpace: INTERNAL
Pset_SpaceCommon - Reference: 계단실2 220; FloorCovering: T30 화강석 물갈기; WallCovering: -; CeilingCovering: 무늬코트뿜칠
BaseQuantities - NetFloorArea: 14.0097 m2; Height: 4100 mm; GrossPerimeter: 16056 mm; GrossFloorArea: 14.0097 m2; GrossVolume: 57.4399 m3
ID 데이터 - 바닥 마감: T30 화강석 물갈기; 번호: 220; 베이스 마감: 목재 걸레받이; 벽 마감: -; 이름: 계단실2; 천장 마감: 무늬코트뿜칠
공정 - 공정: 새 구성
구속조건 - 베이스 간격띄우기: 0 mm; 상한값: 지상 4층; 레벨: 지상 4층; 한계 간격띄우기: 4100 mm
기타 - 거실여부: no; 공정 ID: 0; 카테고리: 룸; 방화구획: yes; 공간분류코드: 33101; 실ID: 409
에너지 해석 - 구역별 실제 전력 부하: 0; 구역별 실제 조명 부하: 0; 기초 전력 부하: 공간 유형별; 기초 조명 부하: 공간 유형별; 사람 수: 0; 열 부하 값: 공간 유형별; 전력 부하 단위: 전력 밀도; 조명 부하 단위: 전력 밀도; 1인당 잠열 취득: 58.6142 W; 1인당 현열 취득: 73.2678 W; 개인별 면적: 28.5714 m2; 실제 전력 부하: 0 W; 실제 조명 부하: 0 W; 지정된 구역별 전력 부하: 13.9931; 지정된 구역별 조명 부하: 10.7639; 지정된 전력 부하: 0 W; 지정된 조명 부하: 0 W; 천장속 조명 방사: 20; 총 개인별 열 취득: 131.882 W
치수 - 계산 높이: 1000 mm; 둘레: 16056 mm; 면적: 14.0097 m2; 무한한 높이: 4100 mm; 체적: 57.4399 m3

# IfcSpace: 계단실2 235:3692958, 235
In: 지상 5층
LongName: 계단실2; InteriorOrExteriorSpace: INTERNAL
Pset_SpaceCommon - Reference: 계단실2 235; FloorCovering: T30 화강석 물갈기; WallCovering: -; CeilingCovering: 무늬코트뿜칠
BaseQuantities - NetFloorArea: 14.0097 m2; Height: 4100 mm; GrossPerimeter: 16056 mm; GrossFloorArea: 14.0097 m2; GrossVolume: 57.4399 m3
ID 데이터 - 바닥 마감: T30 화강석 물갈기; 번호: 235; 베이스 마감: 목재 걸레받이; 벽 마감: -; 이름: 계단실2; 천장 마감: 무늬코트뿜칠
공정 - 공정: 새 구성
구속조건 - 베이스 간격띄우기: 0 mm; 상한값: 지상 5층; 레벨: 지상 5층; 한계 간격띄우기: 4100 mm
기타 - 거실여부: no; 공정 ID: 0; 카테고리: 룸; 방화구획: yes; 공간분류코드: 33101; 실ID: 512
에너지 해석 - 구역별 실제 전력 부하: 0; 구역별 실제 조명 부하: 0; 기초 전력 부하: 공간 유형별; 기초 조명 부하: 공간 유형별; 사람 수: 0; 열 부하 값: 공간 유형별; 전력 부하 단위: 전력 밀도; 조명 부하 단위: 전력 밀도; 1인당 잠열 취득: 58.6142 W; 1인당 현열 취득: 73.2678 W; 개인별 면적: 28.5714 m2; 실제 전력 부하: 0 W; 실제 조명 부하: 0 W; 지정된 구역별 전력 부하: 13.9931; 지정된 구역별 조명 부하: 10.7639; 지정된 전력 부하: 0 W; 지정된 조명 부하: 0 W; 천장속 조명 방사: 20; 총 개인별 열 취득: 131.882 W
치수 - 계산 높이: 1000 mm; 둘레: 16056 mm; 면적: 14.0097 m2; 무한한 높이: 4100 mm; 체적: 57.4399 m3

# IfcSpace: 계단실2 250:3694143, 250
In: 지상 6층
LongName: 계단실2; InteriorOrExteriorSpace: INTERNAL
Pset_SpaceCommon - Reference: 계단실2 250; FloorCovering: T30 화강석 물갈기; WallCovering: -; CeilingCovering: 무늬코트뿜칠
BaseQuantities - NetFloorArea: 14.0132 m2; Height: 4100 mm; GrossPerimeter: 16057.3 mm; GrossFloorArea: 14.0132 m2; GrossVolume: 57.4542 m3
ID 데이터 - 바닥 마감: T30 화강석 물갈기; 번호: 250; 베이스 마감: 목재 걸레받이; 벽 마감: -; 이름: 계단실2; 천장 마감: 무늬코트뿜칠
공정 - 공정: 새 구성
구속조건 - 베이스 간격띄우기: 0 mm; 상한값: 지상 6층; 레벨: 지상 6층; 한계 간격띄우기: 4100 mm
기타 - 거실여부: no; 공정 ID: 0; 카테고리: 룸; 방화구획: yes; 공간분류코드: 33101; 실ID: 612
에너지 해석 - 구역별 실제 전력 부하: 0; 구역별 실제 조명 부하: 0; 기초 전력 부하: 공간 유형별; 기초 조명 부하: 공간 유형별; 사람 수: 0; 열 부하 값: 공간 유형별; 전력 부하 단위: 전력 밀도; 조명 부하 단위: 전력 밀도; 1인당 잠열 취득: 58.6142 W; 1인당 현열 취득: 73.2678 W; 개인별 면적: 28.5714 m2; 실제 전력 부하: 0 W; 실제 조명 부하: 0 W; 지정된 구역별 전력 부하: 13.9931; 지정된 구역별 조명 부하: 10.7639; 지정된 전력 부하: 0 W; 지정된 조명 부하: 0 W; 천장속 조명 방사: 20; 총 개인별 열 취득: 131.882 W
치수 - 계산 높이: 1000 mm; 둘레: 16057.3 mm; 면적: 14.0132 m2; 무한한 높이: 4100 mm; 체적: 57.4542 m3

# IfcSpace: 계단실2 264:3694346, 264
In: 지상 7층
LongName: 계단실2; InteriorOrExteriorSpace: INTERNAL
Pset_SpaceCommon - Reference: 계단실2 264; FloorCovering: T30 화강석 물갈기; WallCovering: -; CeilingCovering: 무늬코트뿜칠
BaseQuantities - NetFloorArea: 14.0097 m2; Height: 4100 mm; GrossPerimeter: 16056 mm; GrossFloorArea: 14.0097 m2; GrossVolume: 57.4399 m3
ID 데이터 - 바닥 마감: T30 화강석 물갈기; 번호: 264; 베이스 마감: 목재 걸레받이; 벽 마감: -; 이름: 계단실2; 천장 마감: 무늬코트뿜칠
공정 - 공정: 새 구성
구속조건 - 베이스 간격띄우기: 0 mm; 상한값: 지상 7층; 레벨: 지상 7층; 한계 간격띄우기: 4100 mm
기타 - 거실여부: no; 공정 ID: 0; 카테고리: 룸; 방화구획: yes; 공간분류코드: 33101; 실ID: 709
에너지 해석 - 구역별 실제 전력 부하: 0; 구역별 실제 조명 부하: 0; 기초 전력 부하: 공간 유형별; 기초 조명 부하: 공간 유형별; 사람 수: 0; 열 부하 값: 공간 유형별; 전력 부하 단위: 전력 밀도; 조명 부하 단위: 전력 밀도; 1인당 잠열 취득: 58.6142 W; 1인당 현열 취득: 73.2678 W; 개인별 면적: 28.5714 m2; 실제 전력 부하: 0 W; 실제 조명 부하: 0 W; 지정된 구역별 전력 부하: 13.9931; 지정된 구역별 조명 부하: 10.7639; 지정된 전력 부하: 0 W; 지정된 조명 부하: 0 W; 천장속 조명 방사: 20; 총 개인별 열 취득: 131.882 W
치수 - 계산 높이: 1000 mm; 둘레: 16056 mm; 면적: 14.0097 m2; 무한한 높이: 4100 mm; 체적: 57.4399 m3

# IfcSpace: 계단실2 282:3694578, 282
In: 지상 8층
LongName: 계단실2; InteriorOrExteriorSpace: INTERNAL
Pset_SpaceCommon - Reference: 계단실2 282; FloorCovering: T30 화강석 물갈기; WallCovering: -; CeilingCovering: 무늬코트뿜칠
BaseQuantities - NetFloorArea: 14.0097 m2; Height: 4100 mm; GrossPerimeter: 16056 mm; GrossFloorArea: 14.0097 m2; GrossVolume: 57.4399 m3
ID 데이터 - 바닥 마감: T30 화강석 물갈기; 번호: 282; 베이스 마감: 목재 걸레받이; 벽 마감: -; 이름: 계단실2; 천장 마감: 무늬코트뿜칠
공정 - 공정: 새 구성
구속조건 - 베이스 간격띄우기: 0 mm; 상한값: 지상 8층; 레벨: 지상 8층; 한계 간격띄우기: 4100 mm
기타 - 거실여부: no; 공정 ID: 0; 카테고리: 룸; 공간분류코드: 33101; 실ID: 809
에너지 해석 - 구역별 실제 전력 부하: 0; 구역별 실제 조명 부하: 0; 기초 전력 부하: 공간 유형별; 기초 조명 부하: 공간 유형별; 사람 수: 0; 열 부하 값: 공간 유형별; 전력 부하 단위: 전력 밀도; 조명 부하 단위: 전력 밀도; 1인당 잠열 취득: 58.6142 W; 1인당 현열 취득: 73.2678 W; 개인별 면적: 28.5714 m2; 실제 전력 부하: 0 W; 실제 조명 부하: 0 W; 지정된 구역별 전력 부하: 13.9931; 지정된 구역별 조명 부하: 10.7639; 지정된 전력 부하: 0 W; 지정된 조명 부하: 0 W; 천장속 조명 방사: 20; 총 개인별 열 취득: 131.882 W
치수 - 계산 높이: 1000 mm; 둘레: 16056 mm; 면적: 14.0097 m2; 무한한 높이: 4100 mm; 체적: 57.4399 m3

# IfcSpace: 계단실2 295:3694747, 295
In: 지상 9층
LongName: 계단실2; InteriorOrExteriorSpace: INTERNAL
Pset_SpaceCommon - Reference: 계단실2 295; FloorCovering: T30 화강석 물갈기; WallCovering: -; CeilingCovering: 무늬코트뿜칠
BaseQuantities - NetFloorArea: 14.0097 m2; Height: 4500 mm; GrossPerimeter: 16056 mm; GrossFloorArea: 14.0097 m2; GrossVolume: 63.0436 m3
ID 데이터 - 바닥 마감: T30 화강석 물갈기; 번호: 295; 베이스 마감: 목재 걸레받이; 벽 마감: -; 이름: 계단실2; 천장 마감: 무늬코트뿜칠
공정 - 공정: 새 구성
구속조건 - 베이스 간격띄우기: 0 mm; 상한값: 지상 9층; 레벨: 지상 9층; 한계 간격띄우기: 4500 mm
기타 - 거실여부: no; 공정 ID: 0; 카테고리: 룸; 공간분류코드: 33101; 실ID: 906
에너지 해석 - 구역별 실제 전력 부하: 0; 구역별 실제 조명 부하: 0; 기초 전력 부하: 공간 유형별; 기초 조명 부하: 공간 유형별; 사람 수: 0; 열 부하 값: 공간 유형별; 전력 부하 단위: 전력 밀도; 조명 부하 단위: 전력 밀도; 1인당 잠열 취득: 58.6142 W; 1인당 현열 취득: 73.2678 W; 개인별 면적: 28.5714 m2; 실제 전력 부하: 0 W; 실제 조명 부하: 0 W; 지정된 구역별 전력 부하: 13.9931; 지정된 구역별 조명 부하: 10.7639; 지정된 전력 부하: 0 W; 지정된 조명 부하: 0 W; 천장속 조명 방사: 20; 총 개인별 열 취득: 131.882 W
치수 - 계산 높이: 1000 mm; 둘레: 16056 mm; 면적: 14.0097 m2; 무한한 높이: 4500 mm; 체적: 63.0436 m3

# IfcSpace: 계단실2 310:3694925, 310
In: 지상 10층
LongName: 계단실2; InteriorOrExteriorSpace: INTERNAL
Pset_SpaceCommon - Reference: 계단실2 310; FloorCovering: T30 화강석 물갈기; WallCovering: -; CeilingCovering: 무늬코트뿜칠
BaseQuantities - NetFloorArea: 14.1519 m2; Height: 5000 mm; GrossPerimeter: 16126 mm; GrossFloorArea: 14.1519 m2; GrossVolume: 70.7595 m3
ID 데이터 - 바닥 마감: T30 화강석 물갈기; 번호: 310; 베이스 마감: 목재 걸레받이; 벽 마감: -; 이름: 계단실2; 천장 마감: 무늬코트뿜칠
공정 - 공정: 새 구성
구속조건 - 베이스 간격띄우기: 0 mm; 상한값: 지상 10층; 레벨: 지상 10층; 한계 간격띄우기: 5000 mm
기타 - 거실여부: no; 공정 ID: 0; 카테고리: 룸; 공간분류코드: 33101; 실ID: 1006
에너지 해석 - 구역별 실제 전력 부하: 0; 구역별 실제 조명 부하: 0; 기초 전력 부하: 공간 유형별; 기초 조명 부하: 공간 유형별; 사람 수: 0; 열 부하 값: 공간 유형별; 전력 부하 단위: 전력 밀도; 조명 부하 단위: 전력 밀도; 1인당 잠열 취득: 58.6142 W; 1인당 현열 취득: 73.2678 W; 개인별 면적: 28.5714 m2; 실제 전력 부하: 0 W; 실제 조명 부하: 0 W; 지정된 구역별 전력 부하: 13.9931; 지정된 구역별 조명 부하: 10.7639; 지정된 전력 부하: 0 W; 지정된 조명 부하: 0 W; 천장속 조명 방사: 20; 총 개인별 열 취득: 131.882 W
치수 - 계산 높이: 1000 mm; 둘레: 16126 mm; 면적: 14.1519 m2; 무한한 높이: 5000 mm; 체적: 70.7595 m3

# IfcSpace: 계단실2 318:3695652, 318
In: 옥탑층
LongName: 계단실2; InteriorOrExteriorSpace: INTERNAL
Pset_SpaceCommon - Reference: 계단실2 318; FloorCovering: T30 화강석 물갈기; WallCovering: -; CeilingCovering: 무늬코트뿜칠
BaseQuantities - NetFloorArea: 14.0198 m2; Height: 3850 mm; GrossPerimeter: 16063.8 mm; GrossFloorArea: 14.0198 m2; GrossVolume: 53.9761 m3
ID 데이터 - 바닥 마감: T30 화강석 물갈기; 번호: 318; 베이스 마감: 목재 걸레받이; 벽 마감: -; 이름: 계단실2; 천장 마감: 무늬코트뿜칠
공정 - 공정: 새 구성
구속조건 - 베이스 간격띄우기: 0 mm; 레벨: 옥탑층; 상한값: 옥탑층; 한계 간격띄우기: 3850 mm
기타 - 거실여부: no; 공정 ID: 0; 카테고리: 룸; 공간분류코드: 33101; 실ID: RF01
에너지 해석 - 구역별 실제 전력 부하: 0; 구역별 실제 조명 부하: 0; 기초 전력 부하: 공간 유형별; 기초 조명 부하: 공간 유형별; 사람 수: 0; 열 부하 값: 공간 유형별; 전력 부하 단위: 전력 밀도; 조명 부하 단위: 전력 밀도; 1인당 잠열 취득: 58.6142 W; 1인당 현열 취득: 73.2678 W; 개인별 면적: 28.5714 m2; 실제 전력 부하: 0 W; 실제 조명 부하: 0 W; 지정된 구역별 전력 부하: 13.9931; 지정된 구역별 조명 부하: 10.7639; 지정된 전력 부하: 0 W; 지정된 조명 부하: 0 W; 천장속 조명 방사: 20; 총 개인별 열 취득: 131.882 W
치수 - 계산 높이: 0 mm; 둘레: 16063.8 mm; 면적: 14.0198 m2; 무한한 높이: 3850 mm; 체적: 53.9761 m3

# IfcSpace: 공용시설 11:7412734, 11
In: 지하1층
LongName: 공용시설; InteriorOrExteriorSpace: INTERNAL; Group: 용도구획
Pset_SpaceCommon - Reference: 공용시설 11
BaseQuantities - NetFloorArea: 1473.79 m2; Height: 6100 mm; GrossFloorArea: 1473.79 m2; GrossVolume: 8990.11 m3
ID 데이터 - 번호: 11; 이름: 공용시설
구속조건 - 레벨: 지하1층
기타 - 카테고리: 면적; 면적 양식 ID: 7408029; 면적 유형: 건물 일반 면적
치수 - 계산 높이: 0 mm; 둘레: 155435 mm; 면적: 1473.79 m2

# IfcSpace: 공용시설 19:7411941, 19
In: 지상 2층
LongName: 공용시설; InteriorOrExteriorSpace: INTERNAL; Group: 용도구획
Pset_SpaceCommon - Reference: 공용시설 19
BaseQuantities - NetFloorArea: 202.51 m2; Height: 4500 mm; GrossFloorArea: 202.51 m2; GrossVolume: 911.293 m3
ID 데이터 - 번호: 19; 이름: 공용시설
구속조건 - 레벨: 지상 2층
기타 - 카테고리: 면적; 면적 양식 ID: 7408029; 면적 유형: 건물 일반 면적
치수 - 계산 높이: 1000 mm; 둘레: 62485 mm; 면적: 202.51 m2

# IfcSpace: 공용시설 1:7411248, 1
In: 지상 1층
LongName: 공용시설; InteriorOrExteriorSpace: INTERNAL; Group: 용도구획
Pset_SpaceCommon - Reference: 공용시설 1
BaseQuantities - NetFloorArea: 300.554 m2; Height: 4800 mm; GrossFloorArea: 300.554 m2; GrossVolume: 1442.66 m3
ID 데이터 - 번호: 1; 이름: 공용시설
구속조건 - 레벨: 지상 1층
기타 - 카테고리: 면적; 면적 양식 ID: 7408029; 면적 유형: 건물 일반 면적
치수 - 계산 높이: 1000 mm; 둘레: 136580 mm; 면적: 300.554 m2

# IfcSpace: 공용시설 21:7412130, 21
In: 지상 4층
LongName: 공용시설; InteriorOrExteriorSpace: INTERNAL; Group: 용도구획
Pset_SpaceCommon - Reference: 공용시설 21
BaseQuantities - NetFloorArea: 202.408 m2; Height: 4100 mm; GrossFloorArea: 202.408 m2; GrossVolume: 829.872 m3
ID 데이터 - 번호: 21; 이름: 공용시설
구속조건 - 레벨: 지상 4층
기타 - 카테고리: 면적; 면적 양식 ID: 7408029; 면적 유형: 건물 일반 면적
치수 - 계산 높이: 1000 mm; 둘레: 62457 mm; 면적: 202.408 m2

# IfcSpace: 공용시설 22:7412207, 22
In: 지상 5층
LongName: 공용시설; InteriorOrExteriorSpace: INTERNAL; Group: 용도구획
Pset_SpaceCommon - Reference: 공용시설 22
BaseQuantities - NetFloorArea: 202.408 m2; Height: 4100 mm; GrossFloorArea: 202.408 m2; GrossVolume: 829.872 m3
ID 데이터 - 번호: 22; 이름: 공용시설
구속조건 - 레벨: 지상 5층
기타 - 카테고리: 면적; 면적 양식 ID: 7408029; 면적 유형: 건물 일반 면적
치수 - 계산 높이: 1000 mm; 둘레: 62457 mm; 면적: 202.408 m2

# IfcSpace: 공용시설 23:7412292, 23
In: 지상 6층
LongName: 공용시설; InteriorOrExteriorSpace: INTERNAL; Group: 용도구획
Pset_SpaceCommon - Reference: 공용시설 23
BaseQuantities - NetFloorArea: 202.408 m2; Height: 4100 mm; GrossFloorArea: 202.408 m2; GrossVolume: 829.872 m3
ID 데이터 - 번호: 23; 이름: 공용시설
구속조건 - 레벨: 지상 6층
기타 - 카테고리: 면적; 면적 양식 ID: 7408029; 면적 유형: 건물 일반 면적
치수 - 계산 높이: 1000 mm; 둘레: 62457 mm; 면적: 202.408 m2

# IfcSpace: 공용시설 24:7412390, 24
In: 지상 7층
LongName: 공용시설; InteriorOrExteriorSpace: INTERNAL; Group: 용도구획
Pset_SpaceCommon - Reference: 공용시설 24
BaseQuantities - NetFloorArea: 202.408 m2; Height: 4100 mm; GrossFloorArea: 202.408 m2; GrossVolume: 829.872 m3
ID 데이터 - 번호: 24; 이름: 공용시설
구속조건 - 레벨: 지상 7층
기타 - 카테고리: 면적; 면적 양식 ID: 7408029; 면적 유형: 건물 일반 면적
치수 - 계산 높이: 1000 mm; 둘레: 62457 mm; 면적: 202.408 m2

# IfcSpace: 공용시설 25:7412480, 25
In: 지상 8층
LongName: 공용시설; InteriorOrExteriorSpace: INTERNAL; Group: 용도구획
Pset_SpaceCommon - Reference: 공용시설 25
BaseQuantities - NetFloorArea: 202.408 m2; Height: 4100 mm; GrossFloorArea: 202.408 m2; GrossVolume: 829.872 m3
ID 데이터 - 번호: 25; 이름: 공용시설
구속조건 - 레벨: 지상 8층
기타 - 카테고리: 면적; 면적 양식 ID: 7408029; 면적 유형: 건물 일반 면적
치수 - 계산 높이: 1000 mm; 둘레: 62457 mm; 면적: 202.408 m2

# IfcSpace: 공용시설 26:7412569, 26
In: 지상 9층
LongName: 공용시설; InteriorOrExteriorSpace: INTERNAL; Group: 용도구획
Pset_SpaceCommon - Reference: 공용시설 26
BaseQuantities - NetFloorArea: 202.408 m2; Height: 4500 mm; GrossFloorArea: 202.408 m2; GrossVolume: 910.836 m3
ID 데이터 - 번호: 26; 이름: 공용시설
구속조건 - 레벨: 지상 9층
기타 - 카테고리: 면적; 면적 양식 ID: 7408029; 면적 유형: 건물 일반 면적
치수 - 계산 높이: 1000 mm; 둘레: 62457 mm; 면적: 202.408 m2

# IfcSpace: 공용시설 27:7412655, 27
In: 지상 10층
LongName: 공용시설; InteriorOrExteriorSpace: INTERNAL; Group: 용도구획
Pset_SpaceCommon - Reference: 공용시설 27
BaseQuantities - NetFloorArea: 202.408 m2; Height: 5000 mm; GrossFloorArea: 202.408 m2; GrossVolume: 1012.04 m3
ID 데이터 - 번호: 27; 이름: 공용시설
구속조건 - 레벨: 지상 10층
기타 - 카테고리: 면적; 면적 양식 ID: 7408029; 면적 유형: 건물 일반 면적
치수 - 계산 높이: 1000 mm; 둘레: 62457 mm; 면적: 202.408 m2

# IfcSpace: 공용시설 3:7412034, 3
In: 지상 3층
LongName: 공용시설; InteriorOrExteriorSpace: INTERNAL; Group: 용도구획
Pset_SpaceCommon - Reference: 공용시설 3
BaseQuantities - NetFloorArea: 202.408 m2; Height: 4100 mm; GrossFloorArea: 202.408 m2; GrossVolume: 829.872 m3
ID 데이터 - 번호: 3; 이름: 공용시설
구속조건 - 레벨: 지상 3층
기타 - 카테고리: 면적; 면적 양식 ID: 7408029; 면적 유형: 건물 일반 면적
치수 - 계산 높이: 1000 mm; 둘레: 62475 mm; 면적: 202.408 m2

# IfcSpace: 공조실 87:5946469, 87
In: 지상 2층
LongName: 공조실; InteriorOrExteriorSpace: INTERNAL
Pset_SpaceCommon - Reference: 공조실 87; FloorCovering: T30 화강석 물갈기; WallCovering: 수성페인트; CeilingCovering: T50유리면흡음판
BaseQuantities - NetFloorArea: 36.2329 m2; Height: 3180 mm; GrossPerimeter: 26156 mm; GrossFloorArea: 36.2329 m2; GrossVolume: 115.22 m3
ID 데이터 - 바닥 마감: T30 화강석 물갈기; 번호: 87; 베이스 마감: 목재 걸레받이; 벽 마감: 수성페인트; 이름: 공조실; 천장 마감: T50유리면흡음판
공정 - 공정: 새 구성
구속조건 - 베이스 간격띄우기: 0 mm; 상한값: 지상 2층; 레벨: 지상 2층; 한계 간격띄우기: 3180 mm
기타 - 거실여부: no; 공정 ID: 0; 카테고리: 룸; 공간분류코드: 33403; 실ID: 213
에너지 해석 - 구역별 실제 전력 부하: 0; 구역별 실제 조명 부하: 0; 기초 전력 부하: 공간 유형별; 기초 조명 부하: 공간 유형별; 사람 수: 0; 열 부하 값: 공간 유형별; 전력 부하 단위: 전력 밀도; 조명 부하 단위: 전력 밀도; 1인당 잠열 취득: 58.6142 W; 1인당 현열 취득: 73.2678 W; 개인별 면적: 28.5714 m2; 실제 전력 부하: 0 W; 실제 조명 부하: 0 W; 지정된 구역별 전력 부하: 13.9931; 지정된 구역별 조명 부하: 10.7639; 지정된 전력 부하: 0 W; 지정된 조명 부하: 0 W; 천장속 조명 방사: 20; 총 개인별 열 취득: 131.882 W
치수 - 계산 높이: 1000 mm; 둘레: 26156 mm; 면적: 36.2329 m2; 무한한 높이: 3180 mm; 체적: 115.22 m3

# IfcSpace: 공조실 88:5946493, 88
In: 지상 9층
LongName: 공조실; InteriorOrExteriorSpace: INTERNAL
Pset_SpaceCommon - Reference: 공조실 88; FloorCovering: T30 화강석 물갈기; WallCovering: 수성페인트; CeilingCovering: T50유리면흡음판
BaseQuantities - NetFloorArea: 36.3664 m2; Height: 3080 mm; GrossPerimeter: 25956 mm; GrossFloorArea: 36.3664 m2; GrossVolume: 112.009 m3
ID 데이터 - 바닥 마감: T30 화강석 물갈기; 번호: 88; 베이스 마감: 목재 걸레받이; 벽 마감: 수성페인트; 이름: 공조실; 천장 마감: T50유리면흡음판
공정 - 공정: 새 구성
구속조건 - 베이스 간격띄우기: 0 mm; 상한값: 지상 9층; 레벨: 지상 9층; 한계 간격띄우기: 3080 mm
기타 - 거실여부: no; 공정 ID: 0; 카테고리: 룸; 공간분류코드: 33403; 실ID: 911
에너지 해석 - 구역별 실제 전력 부하: 0; 구역별 실제 조명 부하: 0; 기초 전력 부하: 공간 유형별; 기초 조명 부하: 공간 유형별; 사람 수: 0; 열 부하 값: 공간 유형별; 전력 부하 단위: 전력 밀도; 조명 부하 단위: 전력 밀도; 1인당 잠열 취득: 58.6142 W; 1인당 현열 취득: 73.2678 W; 개인별 면적: 28.5714 m2; 실제 전력 부하: 0 W; 실제 조명 부하: 0 W; 지정된 구역별 전력 부하: 13.9931; 지정된 구역별 조명 부하: 10.7639; 지정된 전력 부하: 0 W; 지정된 조명 부하: 0 W; 천장속 조명 방사: 20; 총 개인별 열 취득: 131.882 W
치수 - 계산 높이: 1000 mm; 둘레: 25956 mm; 면적: 36.3664 m2; 무한한 높이: 3080 mm; 체적: 112.009 m3

# IfcSpace: 공조실 89:5946502, 89
In: 지상 10층
LongName: 공조실; InteriorOrExteriorSpace: INTERNAL
Pset_SpaceCommon - Reference: 공조실 89; FloorCovering: T30 화강석 물갈기; WallCovering: 수성페인트; CeilingCovering: T50유리면흡음판
BaseQuantities - NetFloorArea: 36.4111 m2; Height: 3580 mm; GrossFloorArea: 36.4111 m2; GrossVolume: 130.352 m3
ID 데이터 - 바닥 마감: T30 화강석 물갈기; 번호: 89; 베이스 마감: 목재 걸레받이; 벽 마감: 수성페인트; 이름: 공조실; 천장 마감: T50유리면흡음판
공정 - 공정: 새 구성
구속조건 - 베이스 간격띄우기: 0 mm; 상한값: 지상 10층; 레벨: 지상 10층; 한계 간격띄우기: 3580 mm
기타 - 거실여부: no; 공정 ID: 0; 카테고리: 룸; 공간분류코드: 33403; 실ID: 1010
에너지 해석 - 구역별 실제 전력 부하: 0; 구역별 실제 조명 부하: 0; 기초 전력 부하: 공간 유형별; 기초 조명 부하: 공간 유형별; 사람 수: 0; 열 부하 값: 공간 유형별; 전력 부하 단위: 전력 밀도; 조명 부하 단위: 전력 밀도; 1인당 잠열 취득: 58.6142 W; 1인당 현열 취득: 73.2678 W; 개인별 면적: 28.5714 m2; 실제 전력 부하: 0 W; 실제 조명 부하: 0 W; 지정된 구역별 전력 부하: 13.9931; 지정된 구역별 조명 부하: 10.7639; 지정된 전력 부하: 0 W; 지정된 조명 부하: 0 W; 천장속 조명 방사: 20; 총 개인별 열 취득: 131.882 W
치수 - 계산 높이: 1000 mm; 둘레: 25920 mm; 면적: 36.4111 m2; 무한한 높이: 3580 mm; 체적: 128.47 m3

# IfcSpace: 공조실 8:5256671, 8
In: 지상 3층
LongName: 공조실; InteriorOrExteriorSpace: INTERNAL
Pset_SpaceCommon - Reference: 공조실 8; FloorCovering: T30 화강석 물갈기; WallCovering: 수성페인트; CeilingCovering: T50유리면흡음판
BaseQuantities - NetFloorArea: 36.2328 m2; Height: 2980 mm; GrossPerimeter: 26156 mm; GrossFloorArea: 36.2328 m2; GrossVolume: 107.974 m3
ID 데이터 - 바닥 마감: T30 화강석 물갈기; 번호: 8; 베이스 마감: 목재 걸레받이; 벽 마감: 수성페인트; 이름: 공조실; 천장 마감: T50유리면흡음판
공정 - 공정: 새 구성
구속조건 - 베이스 간격띄우기: 0 mm; 상한값: 지상 3층; 레벨: 지상 3층; 한계 간격띄우기: 2980 mm
기타 - 거실여부: no; 공정 ID: 0; 카테고리: 룸; 공간분류코드: 33403; 실ID: 320
에너지 해석 - 구역별 실제 전력 부하: 0; 구역별 실제 조명 부하: 0; 기초 전력 부하: 공간 유형별; 기초 조명 부하: 공간 유형별; 사람 수: 0; 열 부하 값: 공간 유형별; 전력 부하 단위: 전력 밀도; 조명 부하 단위: 전력 밀도; 1인당 잠열 취득: 58.6142 W; 1인당 현열 취득: 73.2678 W; 개인별 면적: 28.5714 m2; 실제 전력 부하: 0 W; 실제 조명 부하: 0 W; 지정된 구역별 전력 부하: 13.9931; 지정된 구역별 조명 부하: 10.7639; 지정된 전력 부하: 0 W; 지정된 조명 부하: 0 W; 천장속 조명 방사: 20; 총 개인별 열 취득: 131.882 W
치수 - 계산 높이: 1000 mm; 둘레: 26156 mm; 면적: 36.2328 m2; 무한한 높이: 2980 mm; 체적: 107.974 m3

# IfcSpace: 관람실 174:3691307, 174
In: 지상 2층
LongName: 관람실; InteriorOrExteriorSpace: INTERNAL
Pset_SpaceCommon - Reference: 관람실 174; FloorCovering: T32 테라조타일; WallCovering: 수성페인트; CeilingCovering: T6무석면택스마감
BaseQuantities - NetFloorArea: 105.54 m2; Height: 3180 mm; GrossPerimeter: 42773.2 mm; GrossFloorArea: 105.54 m2; GrossVolume: 335.618 m3
ID 데이터 - 바닥 마감: T32 테라조타일; 번호: 174; 베이스 마감: PVC 걸레받이; 벽 마감: 수성페인트; 이름: 관람실; 천장 마감: T6무석면택스마감
공정 - 공정: 새 구성
구속조건 - 베이스 간격띄우기: 0 mm; 상한값: 지상 2층; 레벨: 지상 2층; 한계 간격띄우기: 3180 mm
기타 - 공정 ID: 0; 카테고리: 룸; 거실여부: yes; 방화구획: yes; 공간분류코드: 33703; 실ID: 202
에너지 해석 - 구역별 실제 전력 부하: 0; 구역별 실제 조명 부하: 0; 기초 전력 부하: 공간 유형별; 기초 조명 부하: 공간 유형별; 사람 수: 0; 열 부하 값: 공간 유형별; 전력 부하 단위: 전력 밀도; 조명 부하 단위: 전력 밀도; 1인당 잠열 취득: 58.6142 W; 1인당 현열 취득: 73.2678 W; 개인별 면적: 28.5714 m2; 실제 전력 부하: 0 W; 실제 조명 부하: 0 W; 지정된 구역별 전력 부하: 13.9931; 지정된 구역별 조명 부하: 10.7639; 지정된 전력 부하: 0 W; 지정된 조명 부하: 0 W; 천장속 조명 방사: 20; 총 개인별 열 취득: 131.882 W
치수 - 계산 높이: 1000 mm; 둘레: 42773.2 mm; 면적: 105.54 m2; 무한한 높이: 3180 mm; 체적: 335.618 m3

# IfcSpace: 관람실 175:3691310, 175
In: 지상 2층
LongName: 관람실; InteriorOrExteriorSpace: INTERNAL
Pset_SpaceCommon - Reference: 관람실 175; FloorCovering: T32 테라조타일; WallCovering: 수성페인트; CeilingCovering: T6무석면택스마감
BaseQuantities - NetFloorArea: 84.9282 m2; Height: 3180 mm; GrossPerimeter: 39336.9 mm; GrossFloorArea: 84.9282 m2; GrossVolume: 270.072 m3
ID 데이터 - 바닥 마감: T32 테라조타일; 번호: 175; 베이스 마감: PVC 걸레받이; 벽 마감: 수성페인트; 이름: 관람실; 천장 마감: T6무석면택스마감
공정 - 공정: 새 구성
구속조건 - 베이스 간격띄우기: 0 mm; 상한값: 지상 2층; 레벨: 지상 2층; 한계 간격띄우기: 3180 mm
기타 - 공정 ID: 0; 카테고리: 룸; 거실여부: yes; 방화구획: yes; 공간분류코드: 33703; 실ID: 203
에너지 해석 - 구역별 실제 전력 부하: 0; 구역별 실제 조명 부하: 0; 기초 전력 부하: 공간 유형별; 기초 조명 부하: 공간 유형별; 사람 수: 0; 열 부하 값: 공간 유형별; 전력 부하 단위: 전력 밀도; 조명 부하 단위: 전력 밀도; 1인당 잠열 취득: 58.6142 W; 1인당 현열 취득: 73.2678 W; 개인별 면적: 28.5714 m2; 실제 전력 부하: 0 W; 실제 조명 부하: 0 W; 지정된 구역별 전력 부하: 13.9931; 지정된 구역별 조명 부하: 10.7639; 지정된 전력 부하: 0 W; 지정된 조명 부하: 0 W; 천장속 조명 방사: 20; 총 개인별 열 취득: 131.882 W
치수 - 계산 높이: 1000 mm; 둘레: 39336.9 mm; 면적: 84.9282 m2; 무한한 높이: 3180 mm; 체적: 270.072 m3

# IfcSpace: 관람실 177:3691317, 177
In: 지상 2층
LongName: 관람실; InteriorOrExteriorSpace: INTERNAL
Pset_SpaceCommon - Reference: 관람실 177; FloorCovering: T32 테라조타일; WallCovering: 수성페인트; CeilingCovering: T6무석면택스마감
BaseQuantities - NetFloorArea: 129.015 m2; Height: 3180 mm; GrossPerimeter: 45737.3 mm; GrossFloorArea: 129.015 m2; GrossVolume: 410.269 m3
ID 데이터 - 바닥 마감: T32 테라조타일; 번호: 177; 베이스 마감: PVC 걸레받이; 벽 마감: 수성페인트; 이름: 관람실; 천장 마감: T6무석면택스마감
공정 - 공정: 새 구성
구속조건 - 베이스 간격띄우기: 0 mm; 상한값: 지상 2층; 레벨: 지상 2층; 한계 간격띄우기: 3180 mm
기타 - 공정 ID: 0; 카테고리: 룸; 거실여부: yes; 방화구획: yes; 공간분류코드: 33703; 실ID: 204
에너지 해석 - 구역별 실제 전력 부하: 0; 구역별 실제 조명 부하: 0; 기초 전력 부하: 공간 유형별; 기초 조명 부하: 공간 유형별; 사람 수: 0; 열 부하 값: 공간 유형별; 전력 부하 단위: 전력 밀도; 조명 부하 단위: 전력 밀도; 1인당 잠열 취득: 58.6142 W; 1인당 현열 취득: 73.2678 W; 개인별 면적: 28.5714 m2; 실제 전력 부하: 0 W; 실제 조명 부하: 0 W; 지정된 구역별 전력 부하: 13.9931; 지정된 구역별 조명 부하: 10.7639; 지정된 전력 부하: 0 W; 지정된 조명 부하: 0 W; 천장속 조명 방사: 20; 총 개인별 열 취득: 131.882 W
치수 - 계산 높이: 1000 mm; 둘레: 45737.3 mm; 면적: 129.015 m2; 무한한 높이: 3180 mm; 체적: 410.269 m3

# IfcSpace: 관람실 179:3691330, 179
In: 지상 2층
LongName: 관람실; InteriorOrExteriorSpace: INTERNAL
Pset_SpaceCommon - Reference: 관람실 179; FloorCovering: T32 테라조타일; WallCovering: 수성페인트; CeilingCovering: T6무석면택스마감
BaseQuantities - NetFloorArea: 146.46 m2; Height: 3180 mm; GrossPerimeter: 52153.9 mm; GrossFloorArea: 146.46 m2; GrossVolume: 465.742 m3
ID 데이터 - 바닥 마감: T32 테라조타일; 번호: 179; 베이스 마감: PVC 걸레받이; 벽 마감: 수성페인트; 이름: 관람실; 천장 마감: T6무석면택스마감
공정 - 공정: 새 구성
구속조건 - 베이스 간격띄우기: 0 mm; 상한값: 지상 2층; 레벨: 지상 2층; 한계 간격띄우기: 3180 mm
기타 - 공정 ID: 0; 카테고리: 룸; 거실여부: yes; 방화구획: yes; 공간분류코드: 33703; 실ID: 205
에너지 해석 - 구역별 실제 전력 부하: 0; 구역별 실제 조명 부하: 0; 기초 전력 부하: 공간 유형별; 기초 조명 부하: 공간 유형별; 사람 수: 0; 열 부하 값: 공간 유형별; 전력 부하 단위: 전력 밀도; 조명 부하 단위: 전력 밀도; 1인당 잠열 취득: 58.6142 W; 1인당 현열 취득: 73.2678 W; 개인별 면적: 28.5714 m2; 실제 전력 부하: 0 W; 실제 조명 부하: 0 W; 지정된 구역별 전력 부하: 13.9931; 지정된 구역별 조명 부하: 10.7639; 지정된 전력 부하: 0 W; 지정된 조명 부하: 0 W; 천장속 조명 방사: 20; 총 개인별 열 취득: 131.882 W
치수 - 계산 높이: 1000 mm; 둘레: 52284.9 mm; 면적: 146.46 m2; 무한한 높이: 3180 mm; 체적: 465.742 m3

# IfcSpace: 관람실 180:3691333, 180
In: 지상 2층
LongName: 관람실; InteriorOrExteriorSpace: INTERNAL
Pset_SpaceCommon - Reference: 관람실 180; FloorCovering: T32 테라조타일; WallCovering: 수성페인트; CeilingCovering: T6무석면택스마감
BaseQuantities - NetFloorArea: 136.607 m2; Height: 3180 mm; GrossPerimeter: 50038.1 mm; GrossFloorArea: 136.607 m2; GrossVolume: 434.41 m3
ID 데이터 - 바닥 마감: T32 테라조타일; 번호: 180; 베이스 마감: PVC 걸레받이; 벽 마감: 수성페인트; 이름: 관람실; 천장 마감: T6무석면택스마감
공정 - 공정: 새 구성
구속조건 - 베이스 간격띄우기: 0 mm; 상한값: 지상 2층; 레벨: 지상 2층; 한계 간격띄우기: 3180 mm
기타 - 공정 ID: 0; 카테고리: 룸; 거실여부: yes; 방화구획: yes; 공간분류코드: 33703; 실ID: 206
에너지 해석 - 구역별 실제 전력 부하: 0; 구역별 실제 조명 부하: 0; 기초 전력 부하: 공간 유형별; 기초 조명 부하: 공간 유형별; 사람 수: 0; 열 부하 값: 공간 유형별; 전력 부하 단위: 전력 밀도; 조명 부하 단위: 전력 밀도; 1인당 잠열 취득: 58.6142 W; 1인당 현열 취득: 73.2678 W; 개인별 면적: 28.5714 m2; 실제 전력 부하: 0 W; 실제 조명 부하: 0 W; 지정된 구역별 전력 부하: 13.9931; 지정된 구역별 조명 부하: 10.7639; 지정된 전력 부하: 0 W; 지정된 조명 부하: 0 W; 천장속 조명 방사: 20; 총 개인별 열 취득: 131.882 W
치수 - 계산 높이: 1000 mm; 둘레: 50038.1 mm; 면적: 136.607 m2; 무한한 높이: 3180 mm; 체적: 434.41 m3

# IfcSpace: 관람실 316:3695511, 316
In: 지상 2층
LongName: 관람실; InteriorOrExteriorSpace: INTERNAL
Pset_SpaceCommon - Reference: 관람실 316; FloorCovering: T32 테라조타일; WallCovering: 수성페인트; CeilingCovering: T6무석면택스마감
BaseQuantities - NetFloorArea: 192.503 m2; Height: 3180 mm; GrossPerimeter: 59072.9 mm; GrossFloorArea: 192.503 m2; GrossVolume: 612.159 m3
ID 데이터 - 바닥 마감: T32 테라조타일; 번호: 316; 베이스 마감: 목재 걸레받이; 벽 마감: 수성페인트; 이름: 관람실; 천장 마감: T6무석면택스마감
공정 - 공정: 새 구성
구속조건 - 베이스 간격띄우기: 0 mm; 상한값: 지상 2층; 레벨: 지상 2층; 한계 간격띄우기: 3180 mm
기타 - 공정 ID: 0; 카테고리: 룸; 거실여부: yes; 공간분류코드: 33703; 실ID: 219
에너지 해석 - 구역별 실제 전력 부하: 0; 구역별 실제 조명 부하: 0; 기초 전력 부하: 공간 유형별; 기초 조명 부하: 공간 유형별; 사람 수: 0; 열 부하 값: 공간 유형별; 전력 부하 단위: 전력 밀도; 조명 부하 단위: 전력 밀도; 1인당 잠열 취득: 58.6142 W; 1인당 현열 취득: 73.2678 W; 개인별 면적: 28.5714 m2; 실제 전력 부하: 0 W; 실제 조명 부하: 0 W; 지정된 구역별 전력 부하: 13.9931; 지정된 구역별 조명 부하: 10.7639; 지정된 전력 부하: 0 W; 지정된 조명 부하: 0 W; 천장속 조명 방사: 20; 총 개인별 열 취득: 131.882 W
치수 - 계산 높이: 1000 mm; 둘레: 59072.9 mm; 면적: 192.503 m2; 무한한 높이: 3180 mm; 체적: 612.159 m3

# IfcSpace: 기계실 126:3690220, 126
In: 지하2층
LongName: 기계실; InteriorOrExteriorSpace: INTERNAL
Pset_SpaceCommon - Reference: 기계실 126; FloorCovering: 에폭시페인트; WallCovering: -; CeilingCovering: 수성페인트 2회
BaseQuantities - NetFloorArea: 322.559 m2; Height: 5650 mm; GrossFloorArea: 322.559 m2; GrossVolume: 1822.46 m3
ID 데이터 - 바닥 마감: 에폭시페인트; 번호: 126; 베이스 마감: 목재 걸레받이; 벽 마감: -; 이름: 기계실; 천장 마감: 수성페인트 2회
공정 - 공정: 새 구성
구속조건 - 상한값: 지하2층; 레벨: 지하2층; 베이스 간격띄우기: -1800 mm; 한계 간격띄우기: 3850 mm
기타 - 거실여부: no; 공정 ID: 0; 카테고리: 룸; 공간분류코드: 33405; 실ID: B202
에너지 해석 - 구역별 실제 전력 부하: 0; 구역별 실제 조명 부하: 0; 기초 전력 부하: 공간 유형별; 기초 조명 부하: 공간 유형별; 사람 수: 0; 열 부하 값: 공간 유형별; 전력 부하 단위: 전력 밀도; 조명 부하 단위: 전력 밀도; 1인당 잠열 취득: 58.6142 W; 1인당 현열 취득: 73.2678 W; 개인별 면적: 28.5714 m2; 실제 전력 부하: 0 W; 실제 조명 부하: 0 W; 지정된 구역별 전력 부하: 13.9931; 지정된 구역별 조명 부하: 10.7639; 지정된 전력 부하: 0 W; 지정된 조명 부하: 0 W; 천장속 조명 방사: 20; 총 개인별 열 취득: 131.882 W
치수 - 계산 높이: 0 mm; 둘레: 73199.8 mm; 면적: 322.559 m2; 무한한 높이: 5650 mm; 체적: 1795.34 m3

# IfcSpace: 기계실 127:3690384, 127
In: 지하2층
LongName: 기계실; InteriorOrExteriorSpace: INTERNAL
Pset_SpaceCommon - Reference: 기계실 127; FloorCovering: 우레탄페인트; WallCovering: -; CeilingCovering: 수성페인트 2회
BaseQuantities - NetFloorArea: 42.9552 m2; Height: 5600 mm; GrossPerimeter: 30673.9 mm; GrossFloorArea: 42.9552 m2; GrossVolume: 240.549 m3
ID 데이터 - 바닥 마감: 우레탄페인트; 번호: 127; 베이스 마감: 목재 걸레받이; 벽 마감: -; 이름: 기계실; 천장 마감: 수성페인트 2회
공정 - 공정: 새 구성
구속조건 - 상한값: 지하2층; 레벨: 지하2층; 베이스 간격띄우기: -1800 mm; 한계 간격띄우기: 3800 mm
기타 - 거실여부: no; 공정 ID: 0; 카테고리: 룸; 공간분류코드: 33405; 실ID: B203
에너지 해석 - 구역별 실제 전력 부하: 0; 구역별 실제 조명 부하: 0; 기초 전력 부하: 공간 유형별; 기초 조명 부하: 공간 유형별; 사람 수: 0; 열 부하 값: 공간 유형별; 전력 부하 단위: 전력 밀도; 조명 부하 단위: 전력 밀도; 1인당 잠열 취득: 58.6142 W; 1인당 현열 취득: 73.2678 W; 개인별 면적: 28.5714 m2; 실제 전력 부하: 0 W; 실제 조명 부하: 0 W; 지정된 구역별 전력 부하: 13.9931; 지정된 구역별 조명 부하: 10.7639; 지정된 전력 부하: 0 W; 지정된 조명 부하: 0 W; 천장속 조명 방사: 20; 총 개인별 열 취득: 131.882 W
치수 - 계산 높이: 0 mm; 둘레: 30573.9 mm; 면적: 42.9552 m2; 무한한 높이: 5600 mm; 체적: 240.549 m3

# IfcSpace: 노대 107:8057453, 107
In: 지상 2층
LongName: 노대; InteriorOrExteriorSpace: INTERNAL
Pset_SpaceCommon - Reference: 노대 107
BaseQuantities - NetFloorArea: 1.57081 m2; Height: 2438.4 mm; GrossPerimeter: 5120.02 mm; GrossFloorArea: 1.57081 m2; GrossVolume: 3.83026 m3
ID 데이터 - 번호: 107; 이름: 노대
공정 - 공정: 새 구성
구속조건 - 베이스 간격띄우기: 0 mm; 한계 간격띄우기: 2438.4 mm; 상한값: 지상 2층; 레벨: 지상 2층
기타 - 거실여부: no; 공정 ID: 0; 카테고리: 룸; 공간분류코드: 노대; 노대여부: yes
에너지 해석 - 구역별 실제 전력 부하: 0; 구역별 실제 조명 부하: 0; 기초 전력 부하: 공간 유형별; 기초 조명 부하: 공간 유형별; 사람 수: 0; 열 부하 값: 공간 유형별; 전력 부하 단위: 전력 밀도; 조명 부하 단위: 전력 밀도; 1인당 잠열 취득: 58.6142 W; 1인당 현열 취득: 73.2678 W; 개인별 면적: 28.5714 m2; 실제 전력 부하: 0 W; 실제 조명 부하: 0 W; 지정된 구역별 전력 부하: 13.9931; 지정된 구역별 조명 부하: 10.7639; 지정된 전력 부하: 0 W; 지정된 조명 부하: 0 W; 천장속 조명 방사: 20; 총 개인별 열 취득: 131.882 W
치수 - 무한한 높이: 2438.4 mm; 계산 높이: 1000 mm; 둘레: 5120.02 mm; 면적: 1.57081 m2; 체적: 3.83026 m3

# IfcSpace: 노대 108:8057705, 108
In: 지상 3층
LongName: 노대; InteriorOrExteriorSpace: INTERNAL
Pset_SpaceCommon - Reference: 노대 108
BaseQuantities - NetFloorArea: 1.57081 m2; Height: 2438.4 mm; GrossPerimeter: 5120.02 mm; GrossFloorArea: 1.57081 m2; GrossVolume: 3.83026 m3
ID 데이터 - 번호: 108; 이름: 노대
공정 - 공정: 새 구성
구속조건 - 베이스 간격띄우기: 0 mm; 한계 간격띄우기: 2438.4 mm; 상한값: 지상 3층; 레벨: 지상 3층
기타 - 거실여부: no; 공정 ID: 0; 카테고리: 룸; 노대여부: yes; 공간분류코드: 노대
에너지 해석 - 구역별 실제 전력 부하: 0; 구역별 실제 조명 부하: 0; 기초 전력 부하: 공간 유형별; 기초 조명 부하: 공간 유형별; 사람 수: 0; 열 부하 값: 공간 유형별; 전력 부하 단위: 전력 밀도; 조명 부하 단위: 전력 밀도; 1인당 잠열 취득: 58.6142 W; 1인당 현열 취득: 73.2678 W; 개인별 면적: 28.5714 m2; 실제 전력 부하: 0 W; 실제 조명 부하: 0 W; 지정된 구역별 전력 부하: 13.9931; 지정된 구역별 조명 부하: 10.7639; 지정된 전력 부하: 0 W; 지정된 조명 부하: 0 W; 천장속 조명 방사: 20; 총 개인별 열 취득: 131.882 W
치수 - 무한한 높이: 2438.4 mm; 계산 높이: 1000 mm; 둘레: 5120.02 mm; 면적: 1.57081 m2; 체적: 3.83026 m3

# IfcSpace: 노대 109:8057802, 109
In: 지상 4층
LongName: 노대; InteriorOrExteriorSpace: INTERNAL
Pset_SpaceCommon - Reference: 노대 109
BaseQuantities - NetFloorArea: 1.57081 m2; Height: 2438.4 mm; GrossPerimeter: 5120.02 mm; GrossFloorArea: 1.57081 m2; GrossVolume: 3.83026 m3
ID 데이터 - 번호: 109; 이름: 노대
공정 - 공정: 새 구성
구속조건 - 베이스 간격띄우기: 0 mm; 한계 간격띄우기: 2438.4 mm; 상한값: 지상 4층; 레벨: 지상 4층
기타 - 거실여부: no; 공정 ID: 0; 카테고리: 룸; 노대여부: yes; 공간분류코드: 노대
에너지 해석 - 구역별 실제 전력 부하: 0; 구역별 실제 조명 부하: 0; 기초 전력 부하: 공간 유형별; 기초 조명 부하: 공간 유형별; 사람 수: 0; 열 부하 값: 공간 유형별; 전력 부하 단위: 전력 밀도; 조명 부하 단위: 전력 밀도; 1인당 잠열 취득: 58.6142 W; 1인당 현열 취득: 73.2678 W; 개인별 면적: 28.5714 m2; 실제 전력 부하: 0 W; 실제 조명 부하: 0 W; 지정된 구역별 전력 부하: 13.9931; 지정된 구역별 조명 부하: 10.7639; 지정된 전력 부하: 0 W; 지정된 조명 부하: 0 W; 천장속 조명 방사: 20; 총 개인별 열 취득: 131.882 W
치수 - 무한한 높이: 2438.4 mm; 계산 높이: 1000 mm; 둘레: 5120.02 mm; 면적: 1.57081 m2; 체적: 3.83026 m3

# IfcSpace: 노대 110:8057921, 110
In: 지상 5층
LongName: 노대; InteriorOrExteriorSpace: INTERNAL
Pset_SpaceCommon - Reference: 노대 110
BaseQuantities - NetFloorArea: 1.57081 m2; Height: 2438.4 mm; GrossPerimeter: 5120.02 mm; GrossFloorArea: 1.57081 m2; GrossVolume: 3.83026 m3
ID 데이터 - 번호: 110; 이름: 노대
공정 - 공정: 새 구성
구속조건 - 베이스 간격띄우기: 0 mm; 한계 간격띄우기: 2438.4 mm; 상한값: 지상 5층; 레벨: 지상 5층
기타 - 거실여부: no; 공정 ID: 0; 카테고리: 룸; 노대여부: yes; 공간분류코드: 노대
에너지 해석 - 구역별 실제 전력 부하: 0; 구역별 실제 조명 부하: 0; 기초 전력 부하: 공간 유형별; 기초 조명 부하: 공간 유형별; 사람 수: 0; 열 부하 값: 공간 유형별; 전력 부하 단위: 전력 밀도; 조명 부하 단위: 전력 밀도; 1인당 잠열 취득: 58.6142 W; 1인당 현열 취득: 73.2678 W; 개인별 면적: 28.5714 m2; 실제 전력 부하: 0 W; 실제 조명 부하: 0 W; 지정된 구역별 전력 부하: 13.9931; 지정된 구역별 조명 부하: 10.7639; 지정된 전력 부하: 0 W; 지정된 조명 부하: 0 W; 천장속 조명 방사: 20; 총 개인별 열 취득: 131.882 W
치수 - 무한한 높이: 2438.4 mm; 계산 높이: 1000 mm; 둘레: 5120.02 mm; 면적: 1.57081 m2; 체적: 3.83026 m3

# IfcSpace: 노대 111:8058019, 111
In: 지상 6층
LongName: 노대; InteriorOrExteriorSpace: INTERNAL
Pset_SpaceCommon - Reference: 노대 111
BaseQuantities - NetFloorArea: 1.57081 m2; Height: 2438.4 mm; GrossPerimeter: 5120.02 mm; GrossFloorArea: 1.57081 m2; GrossVolume: 3.83026 m3
ID 데이터 - 번호: 111; 이름: 노대
공정 - 공정: 새 구성
구속조건 - 베이스 간격띄우기: 0 mm; 한계 간격띄우기: 2438.4 mm; 상한값: 지상 6층; 레벨: 지상 6층
기타 - 거실여부: no; 공정 ID: 0; 카테고리: 룸; 노대여부: yes; 공간분류코드: 노대
에너지 해석 - 구역별 실제 전력 부하: 0; 구역별 실제 조명 부하: 0; 기초 전력 부하: 공간 유형별; 기초 조명 부하: 공간 유형별; 사람 수: 0; 열 부하 값: 공간 유형별; 전력 부하 단위: 전력 밀도; 조명 부하 단위: 전력 밀도; 1인당 잠열 취득: 58.6142 W; 1인당 현열 취득: 73.2678 W; 개인별 면적: 28.5714 m2; 실제 전력 부하: 0 W; 실제 조명 부하: 0 W; 지정된 구역별 전력 부하: 13.9931; 지정된 구역별 조명 부하: 10.7639; 지정된 전력 부하: 0 W; 지정된 조명 부하: 0 W; 천장속 조명 방사: 20; 총 개인별 열 취득: 131.882 W
치수 - 무한한 높이: 2438.4 mm; 계산 높이: 1000 mm; 둘레: 5120.02 mm; 면적: 1.57081 m2; 체적: 3.83026 m3

# IfcSpace: 노대 112:8058104, 112
In: 지상 7층
LongName: 노대; InteriorOrExteriorSpace: INTERNAL
Pset_SpaceCommon - Reference: 노대 112
BaseQuantities - NetFloorArea: 1.57081 m2; Height: 2438.4 mm; GrossPerimeter: 5120.02 mm; GrossFloorArea: 1.57081 m2; GrossVolume: 3.83026 m3
ID 데이터 - 번호: 112; 이름: 노대
공정 - 공정: 새 구성
구속조건 - 베이스 간격띄우기: 0 mm; 한계 간격띄우기: 2438.4 mm; 상한값: 지상 7층; 레벨: 지상 7층
기타 - 거실여부: no; 공정 ID: 0; 카테고리: 룸; 노대여부: yes; 공간분류코드: 노대
에너지 해석 - 구역별 실제 전력 부하: 0; 구역별 실제 조명 부하: 0; 기초 전력 부하: 공간 유형별; 기초 조명 부하: 공간 유형별; 사람 수: 0; 열 부하 값: 공간 유형별; 전력 부하 단위: 전력 밀도; 조명 부하 단위: 전력 밀도; 1인당 잠열 취득: 58.6142 W; 1인당 현열 취득: 73.2678 W; 개인별 면적: 28.5714 m2; 실제 전력 부하: 0 W; 실제 조명 부하: 0 W; 지정된 구역별 전력 부하: 13.9931; 지정된 구역별 조명 부하: 10.7639; 지정된 전력 부하: 0 W; 지정된 조명 부하: 0 W; 천장속 조명 방사: 20; 총 개인별 열 취득: 131.882 W
치수 - 무한한 높이: 2438.4 mm; 계산 높이: 1000 mm; 둘레: 5120.02 mm; 면적: 1.57081 m2; 체적: 3.83026 m3

# IfcSpace: 노대 113:8058205, 113
In: 지상 8층
LongName: 노대; InteriorOrExteriorSpace: INTERNAL
Pset_SpaceCommon - Reference: 노대 113
BaseQuantities - NetFloorArea: 1.57081 m2; Height: 2438.4 mm; GrossPerimeter: 5120.02 mm; GrossFloorArea: 1.57081 m2; GrossVolume: 3.83026 m3
ID 데이터 - 번호: 113; 이름: 노대
공정 - 공정: 새 구성
구속조건 - 베이스 간격띄우기: 0 mm; 한계 간격띄우기: 2438.4 mm; 상한값: 지상 8층; 레벨: 지상 8층
기타 - 거실여부: no; 공정 ID: 0; 카테고리: 룸; 노대여부: yes; 공간분류코드: 노대
에너지 해석 - 구역별 실제 전력 부하: 0; 구역별 실제 조명 부하: 0; 기초 전력 부하: 공간 유형별; 기초 조명 부하: 공간 유형별; 사람 수: 0; 열 부하 값: 공간 유형별; 전력 부하 단위: 전력 밀도; 조명 부하 단위: 전력 밀도; 1인당 잠열 취득: 58.6142 W; 1인당 현열 취득: 73.2678 W; 개인별 면적: 28.5714 m2; 실제 전력 부하: 0 W; 실제 조명 부하: 0 W; 지정된 구역별 전력 부하: 13.9931; 지정된 구역별 조명 부하: 10.7639; 지정된 전력 부하: 0 W; 지정된 조명 부하: 0 W; 천장속 조명 방사: 20; 총 개인별 열 취득: 131.882 W
치수 - 무한한 높이: 2438.4 mm; 계산 높이: 1000 mm; 둘레: 5069.24 mm; 면적: 1.57081 m2; 체적: 3.83026 m3

# IfcSpace: 노대 114:8058286, 114
In: 지상 9층
LongName: 노대; InteriorOrExteriorSpace: INTERNAL
Pset_SpaceCommon - Reference: 노대 114
BaseQuantities - NetFloorArea: 1.57081 m2; Height: 2438.4 mm; GrossPerimeter: 5120.02 mm; GrossFloorArea: 1.57081 m2; GrossVolume: 3.83026 m3
ID 데이터 - 번호: 114; 이름: 노대
공정 - 공정: 새 구성
구속조건 - 베이스 간격띄우기: 0 mm; 한계 간격띄우기: 2438.4 mm; 상한값: 지상 9층; 레벨: 지상 9층
기타 - 거실여부: no; 공정 ID: 0; 카테고리: 룸; 노대여부: yes; 공간분류코드: 노대
에너지 해석 - 구역별 실제 전력 부하: 0; 구역별 실제 조명 부하: 0; 기초 전력 부하: 공간 유형별; 기초 조명 부하: 공간 유형별; 사람 수: 0; 열 부하 값: 공간 유형별; 전력 부하 단위: 전력 밀도; 조명 부하 단위: 전력 밀도; 1인당 잠열 취득: 58.6142 W; 1인당 현열 취득: 73.2678 W; 개인별 면적: 28.5714 m2; 실제 전력 부하: 0 W; 실제 조명 부하: 0 W; 지정된 구역별 전력 부하: 13.9931; 지정된 구역별 조명 부하: 10.7639; 지정된 전력 부하: 0 W; 지정된 조명 부하: 0 W; 천장속 조명 방사: 20; 총 개인별 열 취득: 131.882 W
치수 - 무한한 높이: 2438.4 mm; 계산 높이: 1000 mm; 둘레: 5120.02 mm; 면적: 1.57081 m2; 체적: 3.83026 m3

# IfcSpace: 노대 115:8058419, 115
In: 지상 10층
LongName: 노대; InteriorOrExteriorSpace: INTERNAL
Pset_SpaceCommon - Reference: 노대 115
BaseQuantities - NetFloorArea: 1.79676 m2; Height: 2438.4 mm; GrossFloorArea: 1.79676 m2; GrossVolume: 4.38122 m3
ID 데이터 - 번호: 115; 이름: 노대
공정 - 공정: 새 구성
구속조건 - 베이스 간격띄우기: 0 mm; 한계 간격띄우기: 2438.4 mm; 상한값: 지상 10층; 레벨: 지상 10층
기타 - 거실여부: no; 공정 ID: 0; 카테고리: 룸; 노대여부: yes; 공간분류코드: 노대
에너지 해석 - 구역별 실제 전력 부하: 0; 구역별 실제 조명 부하: 0; 기초 전력 부하: 공간 유형별; 기초 조명 부하: 공간 유형별; 사람 수: 0; 열 부하 값: 공간 유형별; 전력 부하 단위: 전력 밀도; 조명 부하 단위: 전력 밀도; 1인당 잠열 취득: 58.6142 W; 1인당 현열 취득: 73.2678 W; 개인별 면적: 28.5714 m2; 실제 전력 부하: 0 W; 실제 조명 부하: 0 W; 지정된 구역별 전력 부하: 13.9931; 지정된 구역별 조명 부하: 10.7639; 지정된 전력 부하: 0 W; 지정된 조명 부하: 0 W; 천장속 조명 방사: 20; 총 개인별 열 취득: 131.882 W
치수 - 무한한 높이: 2438.4 mm; 계산 높이: 1000 mm; 둘레: 5430.02 mm; 면적: 1.79676 m2; 체적: 4.23748 m3

# IfcSpace: 다목적화장실 188:3691555, 188
In: 지상 2층
LongName: 다목적화장실; InteriorOrExteriorSpace: INTERNAL
Pset_SpaceCommon - Reference: 다목적화장실 188; FloorCovering: 자기질타일(바탕32, 압착8); WallCovering: 도기질타일(200x200x8T); CeilingCovering: 열경화성 천정재 (300x300x1.2T)
BaseQuantities - NetFloorArea: 16.7538 m2; Height: 2710 mm; GrossPerimeter: 21529.9 mm; GrossFloorArea: 16.7538 m2; GrossVolume: 45.4027 m3
ID 데이터 - 바닥 마감: 자기질타일(바탕32, 압착8); 번호: 188; 베이스 마감: 목재 걸레받이; 벽 마감: 도기질타일(200x200x8T); 이름: 다목적화장실; 천장 마감: 열경화성 천정재 (300x300x1.2T)
공정 - 공정: 새 구성
구속조건 - 상한값: 지상 2층; 레벨: 지상 2층; 베이스 간격띄우기: -50 mm; 한계 간격띄우기: 2660 mm
기타 - 공정 ID: 0; 카테고리: 룸; 거실여부: yes; 방화구획: yes; 공간분류코드: 33234; 실ID: 210; 장애인용: yes
에너지 해석 - 구역별 실제 전력 부하: 0; 구역별 실제 조명 부하: 0; 기초 전력 부하: 공간 유형별; 기초 조명 부하: 공간 유형별; 사람 수: 0; 열 부하 값: 공간 유형별; 전력 부하 단위: 전력 밀도; 조명 부하 단위: 전력 밀도; 1인당 잠열 취득: 58.6142 W; 1인당 현열 취득: 73.2678 W; 개인별 면적: 28.5714 m2; 실제 전력 부하: 0 W; 실제 조명 부하: 0 W; 지정된 구역별 전력 부하: 13.9931; 지정된 구역별 조명 부하: 10.7639; 지정된 전력 부하: 0 W; 지정된 조명 부하: 0 W; 천장속 조명 방사: 20; 총 개인별 열 취득: 131.882 W
치수 - 계산 높이: 1000 mm; 둘레: 21529.9 mm; 면적: 16.7538 m2; 무한한 높이: 2710 mm; 체적: 45.4027 m3

# IfcSpace: 면적 4:5234739, 4
In: 지하2층
LongName: 면적; InteriorOrExteriorSpace: INTERNAL; Group: Gross Building
Pset_SpaceCommon - Reference: 면적 4
BaseQuantities - NetFloorArea: 90.1996 m2; Height: 4000 mm; GrossFloorArea: 90.1996 m2; GrossVolume: 360.798 m3
ID 데이터 - 번호: 4; 이름: 면적
구속조건 - 레벨: 지하2층
기타 - 카테고리: 면적; 면적 양식 ID: 482392; 면적 유형: 건축 면적
치수 - 계산 높이: 0 mm; 둘레: 38399.9 mm; 면적: 90.1996 m2

# IfcSpace: 문화 및 집회시설 중 공연장 2:7411935, 2
In: 지상 2층
LongName: 문화 및 집회시설 중 공연장; InteriorOrExteriorSpace: INTERNAL; Group: 용도구획
Pset_SpaceCommon - Reference: 문화 및 집회시설 중 공연장 2
BaseQuantities - NetFloorArea: 947.459 m2; Height: 4500 mm; GrossFloorArea: 947.459 m2; GrossVolume: 4263.57 m3
ID 데이터 - 번호: 2; 이름: 문화 및 집회시설 중 공연장
구속조건 - 레벨: 지상 2층
기타 - 카테고리: 면적; 면적 양식 ID: 7408029; 면적 유형: 건물 일반 면적; 용도분류코드: 050100
치수 - 계산 높이: 1000 mm; 둘레: 187835 mm; 면적: 947.459 m2

# IfcSpace: 방재실 135:3690477, 135
In: 지하2층
LongName: 방재실; InteriorOrExteriorSpace: INTERNAL
Pset_SpaceCommon - Reference: 방재실 135; FloorCovering: 우레탄페인트; WallCovering: -; CeilingCovering: 수성페인트 2회
BaseQuantities - NetFloorArea: 19.1511 m2; Height: 3850 mm; GrossPerimeter: 18408.3 mm; GrossFloorArea: 19.1511 m2; GrossVolume: 73.7318 m3
ID 데이터 - 바닥 마감: 우레탄페인트; 번호: 135; 베이스 마감: 목재 걸레받이; 벽 마감: -; 이름: 방재실; 천장 마감: 수성페인트 2회
공정 - 공정: 새 구성
구속조건 - 베이스 간격띄우기: 0 mm; 상한값: 지하2층; 레벨: 지하2층; 한계 간격띄우기: 3850 mm
기타 - 공정 ID: 0; 카테고리: 룸; 거실여부: yes; 공간분류코드: 33401; 실ID: B211
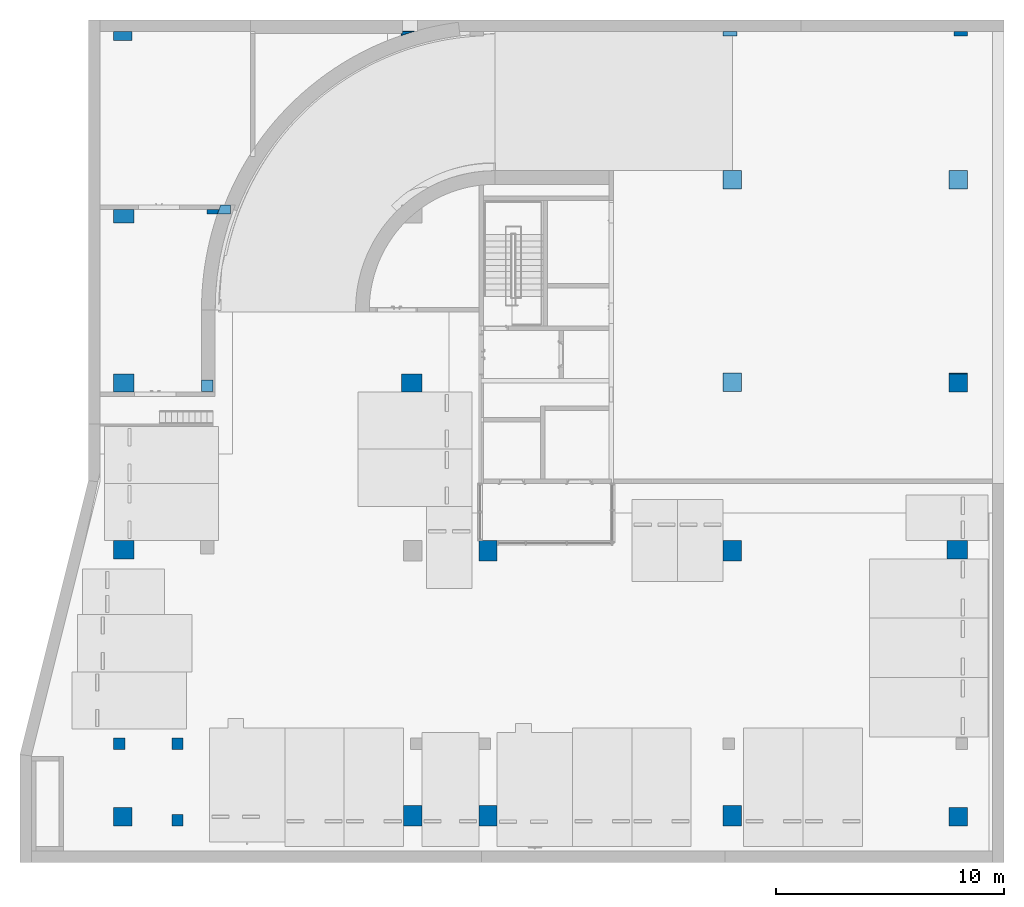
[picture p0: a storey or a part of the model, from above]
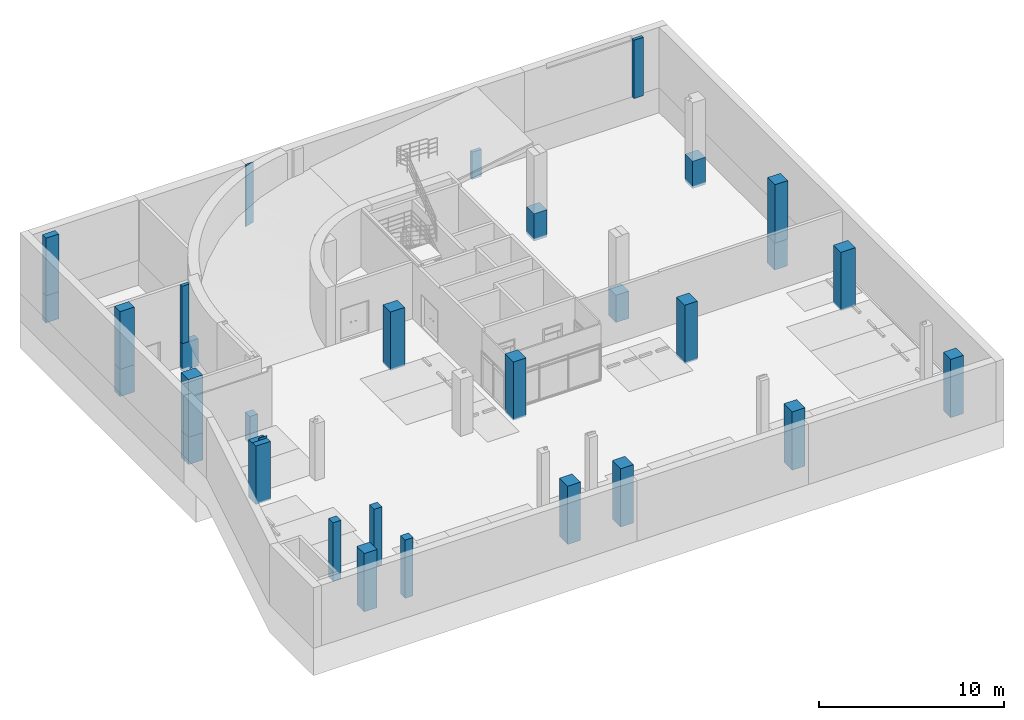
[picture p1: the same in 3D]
Properties of the parts of a building model (IFC2X3), part 2 of 39

# IfcSpace: 방재실 135:3690477, 135
에너지 해석 - 구역별 실제 전력 부하: 0; 구역별 실제 조명 부하: 0; 기초 전력 부하: 공간 유형별; 기초 조명 부하: 공간 유형별; 사람 수: 0; 열 부하 값: 공간 유형별; 전력 부하 단위: 전력 밀도; 조명 부하 단위: 전력 밀도; 1인당 잠열 취득: 58.6142 W; 1인당 현열 취득: 73.2678 W; 개인별 면적: 28.5714 m2; 실제 전력 부하: 0 W; 실제 조명 부하: 0 W; 지정된 구역별 전력 부하: 13.9931; 지정된 구역별 조명 부하: 10.7639; 지정된 전력 부하: 0 W; 지정된 조명 부하: 0 W; 천장속 조명 방사: 20; 총 개인별 열 취득: 131.882 W
치수 - 계산 높이: 0 mm; 둘레: 18336.3 mm; 면적: 19.1511 m2; 무한한 높이: 3850 mm; 체적: 73.7251 m3

# IfcSpace: 방재실 142:3691077, 142
In: 지하1층
LongName: 방재실; InteriorOrExteriorSpace: INTERNAL
Pset_SpaceCommon - Reference: 방재실 142; FloorCovering: 우레탄페인트; WallCovering: -; CeilingCovering: 수성페인트 2회
BaseQuantities - NetFloorArea: 19.1511 m2; Height: 5900 mm; GrossPerimeter: 18408.3 mm; GrossFloorArea: 19.1511 m2; GrossVolume: 112.992 m3
ID 데이터 - 바닥 마감: 우레탄페인트; 번호: 142; 베이스 마감: 목재 걸레받이; 벽 마감: -; 이름: 방재실; 천장 마감: 수성페인트 2회
공정 - 공정: 새 구성
구속조건 - 베이스 간격띄우기: 0 mm; 상한값: 지하1층; 레벨: 지하1층; 한계 간격띄우기: 5900 mm
기타 - 공정 ID: 0; 카테고리: 룸; 거실여부: yes; 공간분류코드: 33401; 실ID: B105
에너지 해석 - 구역별 실제 전력 부하: 0; 구역별 실제 조명 부하: 0; 기초 전력 부하: 공간 유형별; 기초 조명 부하: 공간 유형별; 사람 수: 0; 열 부하 값: 공간 유형별; 전력 부하 단위: 전력 밀도; 조명 부하 단위: 전력 밀도; 1인당 잠열 취득: 58.6142 W; 1인당 현열 취득: 73.2678 W; 개인별 면적: 28.5714 m2; 실제 전력 부하: 0 W; 실제 조명 부하: 0 W; 지정된 구역별 전력 부하: 13.9931; 지정된 구역별 조명 부하: 10.7639; 지정된 전력 부하: 0 W; 지정된 조명 부하: 0 W; 천장속 조명 방사: 20; 총 개인별 열 취득: 131.882 W
치수 - 계산 높이: 0 mm; 둘레: 18336.3 mm; 면적: 19.1511 m2; 무한한 높이: 5900 mm; 체적: 112.981 m3

# IfcSpace: 방풍실1 167:3691271, 167
In: 지상 1층
LongName: 방풍실1; InteriorOrExteriorSpace: INTERNAL
Pset_SpaceCommon - Reference: 방풍실1 167; FloorCovering: T30 화강석 물갈기; WallCovering: 수성페인트; CeilingCovering: T6무석면택스마감
BaseQuantities - NetFloorArea: 28.0679 m2; Height: 3580 mm; GrossPerimeter: 21622.9 mm; GrossFloorArea: 28.0679 m2; GrossVolume: 100.483 m3
ID 데이터 - 바닥 마감: T30 화강석 물갈기; 번호: 167; 베이스 마감: 목재 걸레받이; 벽 마감: 수성페인트; 이름: 방풍실1; 천장 마감: T6무석면택스마감
공정 - 공정: 새 구성
구속조건 - 베이스 간격띄우기: 0 mm; 상한값: 지상 1층; 레벨: 지상 1층; 한계 간격띄우기: 3580 mm
기타 - 거실여부: no; 공정 ID: 0; 카테고리: 룸; 공간분류코드: 33409; 실ID: 119
에너지 해석 - 구역별 실제 전력 부하: 0; 구역별 실제 조명 부하: 0; 기초 전력 부하: 공간 유형별; 기초 조명 부하: 공간 유형별; 사람 수: 0; 열 부하 값: 공간 유형별; 전력 부하 단위: 전력 밀도; 조명 부하 단위: 전력 밀도; 1인당 잠열 취득: 58.6142 W; 1인당 현열 취득: 73.2678 W; 개인별 면적: 28.5714 m2; 실제 전력 부하: 0 W; 실제 조명 부하: 0 W; 지정된 구역별 전력 부하: 13.9931; 지정된 구역별 조명 부하: 10.7639; 지정된 전력 부하: 0 W; 지정된 조명 부하: 0 W; 천장속 조명 방사: 20; 총 개인별 열 취득: 131.882 W
치수 - 계산 높이: 1000 mm; 둘레: 21622.9 mm; 면적: 28.0679 m2; 무한한 높이: 3580 mm; 체적: 100.483 m3

# IfcSpace: 방풍실2 172:3691295, 172
In: 지상 1층
LongName: 방풍실2; InteriorOrExteriorSpace: INTERNAL
Pset_SpaceCommon - Reference: 방풍실2 172; FloorCovering: T30 화강석 물갈기; WallCovering: 수성페인트; CeilingCovering: T6무석면택스마감
BaseQuantities - NetFloorArea: 5.80504 m2; Height: 3580 mm; GrossPerimeter: 9644.03 mm; GrossFloorArea: 5.80504 m2; GrossVolume: 20.782 m3
ID 데이터 - 바닥 마감: T30 화강석 물갈기; 번호: 172; 베이스 마감: 목재 걸레받이; 벽 마감: 수성페인트; 이름: 방풍실2; 천장 마감: T6무석면택스마감
공정 - 공정: 새 구성
구속조건 - 베이스 간격띄우기: 0 mm; 상한값: 지상 1층; 레벨: 지상 1층; 한계 간격띄우기: 3580 mm
기타 - 거실여부: no; 공정 ID: 0; 카테고리: 룸; 방화구획: yes; 공간분류코드: 33409; 실ID: 123
에너지 해석 - 구역별 실제 전력 부하: 0; 구역별 실제 조명 부하: 0; 기초 전력 부하: 공간 유형별; 기초 조명 부하: 공간 유형별; 사람 수: 0; 열 부하 값: 공간 유형별; 전력 부하 단위: 전력 밀도; 조명 부하 단위: 전력 밀도; 1인당 잠열 취득: 58.6142 W; 1인당 현열 취득: 73.2678 W; 개인별 면적: 28.5714 m2; 실제 전력 부하: 0 W; 실제 조명 부하: 0 W; 지정된 구역별 전력 부하: 13.9931; 지정된 구역별 조명 부하: 10.7639; 지정된 전력 부하: 0 W; 지정된 조명 부하: 0 W; 천장속 조명 방사: 20; 총 개인별 열 취득: 131.882 W
치수 - 계산 높이: 1000 mm; 둘레: 9644.03 mm; 면적: 5.80504 m2; 무한한 높이: 3580 mm; 체적: 20.782 m3

# IfcSpace: 방풍실3 86:5509937, 86
In: 지상 1층
LongName: 방풍실3; InteriorOrExteriorSpace: INTERNAL
Pset_SpaceCommon - Reference: 방풍실3 86; FloorCovering: T30 화강석 물갈기; WallCovering: 수성페인트; CeilingCovering: T6무석면택스마감
BaseQuantities - NetFloorArea: 5.4947 m2; Height: 4080 mm; GrossPerimeter: 9387.98 mm; GrossFloorArea: 5.4947 m2; GrossVolume: 22.4184 m3
ID 데이터 - 바닥 마감: T30 화강석 물갈기; 번호: 86; 베이스 마감: 목재 걸레받이; 벽 마감: 수성페인트; 이름: 방풍실3; 천장 마감: T6무석면택스마감
공정 - 공정: 새 구성
구속조건 - 상한값: 지상 1층; 레벨: 지상 1층; 베이스 간격띄우기: -500 mm; 한계 간격띄우기: 3580 mm
기타 - 거실여부: no; 공정 ID: 0; 카테고리: 룸; 공간분류코드: 33409; 실ID: 124
에너지 해석 - 구역별 실제 전력 부하: 0; 구역별 실제 조명 부하: 0; 기초 전력 부하: 공간 유형별; 기초 조명 부하: 공간 유형별; 사람 수: 0; 열 부하 값: 공간 유형별; 전력 부하 단위: 전력 밀도; 조명 부하 단위: 전력 밀도; 1인당 잠열 취득: 58.6142 W; 1인당 현열 취득: 73.2678 W; 개인별 면적: 28.5714 m2; 실제 전력 부하: 0 W; 실제 조명 부하: 0 W; 지정된 구역별 전력 부하: 13.9931; 지정된 구역별 조명 부하: 10.7639; 지정된 전력 부하: 0 W; 지정된 조명 부하: 0 W; 천장속 조명 방사: 20; 총 개인별 열 취득: 131.882 W
치수 - 계산 높이: 1000 mm; 둘레: 9387.98 mm; 면적: 5.4947 m2; 무한한 높이: 4080 mm; 체적: 22.4184 m3

# IfcSpace: 방화구획 17:7414684, 17
In: 지상 2층
LongName: 방화구획; InteriorOrExteriorSpace: INTERNAL; Group: 방화구획
Pset_SpaceCommon - Reference: 방화구획 17
BaseQuantities - NetFloorArea: 217.635 m2; Height: 4500 mm; GrossFloorArea: 217.635 m2; GrossVolume: 979.359 m3
ID 데이터 - 번호: 17; 이름: 방화구획
구속조건 - 레벨: 지상 2층
기타 - 카테고리: 면적; 면적 양식 ID: 7408038; 면적 유형: 건축 면적
치수 - 계산 높이: 1000 mm; 둘레: 71832.6 mm; 면적: 217.635 m2

# IfcSpace: 방화구획 18:7415053, 18
In: 지상 2층
LongName: 방화구획; InteriorOrExteriorSpace: INTERNAL; Group: 방화구획
Pset_SpaceCommon - Reference: 방화구획 18
BaseQuantities - NetFloorArea: 320.192 m2; Height: 4500 mm; GrossFloorArea: 320.192 m2; GrossVolume: 1440.87 m3
ID 데이터 - 번호: 18; 이름: 방화구획
구속조건 - 레벨: 지상 2층
기타 - 카테고리: 면적; 면적 양식 ID: 7408038; 면적 유형: 건축 면적
치수 - 계산 높이: 1000 mm; 둘레: 95381.3 mm; 면적: 320.192 m2

# IfcSpace: 방화구획 19:7415055, 19
In: 지상 2층
LongName: 방화구획; InteriorOrExteriorSpace: INTERNAL; Group: 방화구획
Pset_SpaceCommon - Reference: 방화구획 19
BaseQuantities - NetFloorArea: 464.866 m2; Height: 4500 mm; GrossFloorArea: 464.866 m2; GrossVolume: 2091.9 m3
ID 데이터 - 번호: 19; 이름: 방화구획
구속조건 - 레벨: 지상 2층
기타 - 카테고리: 면적; 면적 양식 ID: 7408038; 면적 유형: 건축 면적
치수 - 계산 높이: 1000 mm; 둘레: 99600 mm; 면적: 464.866 m2

# IfcSpace: 방화구획 20:7415057, 20
In: 지상 2층
LongName: 방화구획; InteriorOrExteriorSpace: INTERNAL; Group: 방화구획
Pset_SpaceCommon - Reference: 방화구획 20
BaseQuantities - NetFloorArea: 165.435 m2; Height: 4500 mm; GrossFloorArea: 165.435 m2; GrossVolume: 744.458 m3
ID 데이터 - 번호: 20; 이름: 방화구획
구속조건 - 레벨: 지상 2층
기타 - 카테고리: 면적; 면적 양식 ID: 7408038; 면적 유형: 건축 면적
치수 - 계산 높이: 1000 mm; 둘레: 61208.7 mm; 면적: 165.435 m2

# IfcSpace: 방화구획 25:7415132, 25
In: 지상 3층
LongName: 방화구획; InteriorOrExteriorSpace: INTERNAL; Group: 방화구획
Pset_SpaceCommon - Reference: 방화구획 25
BaseQuantities - NetFloorArea: 217.635 m2; Height: 4100 mm; GrossFloorArea: 217.635 m2; GrossVolume: 892.305 m3
ID 데이터 - 번호: 25; 이름: 방화구획
구속조건 - 레벨: 지상 3층
기타 - 카테고리: 면적; 면적 양식 ID: 7408038; 면적 유형: 건축 면적
치수 - 계산 높이: 1000 mm; 둘레: 71832.6 mm; 면적: 217.635 m2

# IfcSpace: 방화구획 26:7415137, 26
In: 지상 3층
LongName: 방화구획; InteriorOrExteriorSpace: INTERNAL; Group: 방화구획
Pset_SpaceCommon - Reference: 방화구획 26
BaseQuantities - NetFloorArea: 321.211 m2; Height: 4100 mm; GrossFloorArea: 321.211 m2; GrossVolume: 1316.97 m3
ID 데이터 - 번호: 26; 이름: 방화구획
구속조건 - 레벨: 지상 3층
기타 - 카테고리: 면적; 면적 양식 ID: 7408038; 면적 유형: 건축 면적
치수 - 계산 높이: 1000 mm; 둘레: 95456.2 mm; 면적: 321.211 m2

# IfcSpace: 방화구획 27:7415138, 27
In: 지상 3층
LongName: 방화구획; InteriorOrExteriorSpace: INTERNAL; Group: 방화구획
Pset_SpaceCommon - Reference: 방화구획 27
BaseQuantities - NetFloorArea: 467.358 m2; Height: 4100 mm; GrossFloorArea: 467.358 m2; GrossVolume: 1916.17 m3
ID 데이터 - 번호: 27; 이름: 방화구획
구속조건 - 레벨: 지상 3층
기타 - 카테고리: 면적; 면적 양식 ID: 7408038; 면적 유형: 건축 면적
치수 - 계산 높이: 1000 mm; 둘레: 99600 mm; 면적: 467.358 m2

# IfcSpace: 방화구획 28:7415139, 28
In: 지상 3층
LongName: 방화구획; InteriorOrExteriorSpace: INTERNAL; Group: 방화구획
Pset_SpaceCommon - Reference: 방화구획 28
BaseQuantities - NetFloorArea: 166.055 m2; Height: 4100 mm; GrossFloorArea: 166.055 m2; GrossVolume: 680.826 m3
ID 데이터 - 번호: 28; 이름: 방화구획
구속조건 - 레벨: 지상 3층
기타 - 카테고리: 면적; 면적 양식 ID: 7408038; 면적 유형: 건축 면적
치수 - 계산 높이: 1000 mm; 둘레: 61208.7 mm; 면적: 166.055 m2

# IfcSpace: 방화구획 29:7415169, 29
In: 지상 4층
LongName: 방화구획; InteriorOrExteriorSpace: INTERNAL; Group: 방화구획
Pset_SpaceCommon - Reference: 방화구획 29
BaseQuantities - NetFloorArea: 217.635 m2; Height: 4100 mm; GrossFloorArea: 217.635 m2; GrossVolume: 892.305 m3
ID 데이터 - 번호: 29; 이름: 방화구획
구속조건 - 레벨: 지상 4층
기타 - 카테고리: 면적; 면적 양식 ID: 7408038; 면적 유형: 건축 면적
치수 - 계산 높이: 1000 mm; 둘레: 71752.6 mm; 면적: 217.635 m2

# IfcSpace: 방화구획 30:7415174, 30
In: 지상 4층
LongName: 방화구획; InteriorOrExteriorSpace: INTERNAL; Group: 방화구획
Pset_SpaceCommon - Reference: 방화구획 30
BaseQuantities - NetFloorArea: 323.618 m2; Height: 4100 mm; GrossFloorArea: 323.618 m2; GrossVolume: 1326.83 m3
ID 데이터 - 번호: 30; 이름: 방화구획
구속조건 - 레벨: 지상 4층
기타 - 카테고리: 면적; 면적 양식 ID: 7408038; 면적 유형: 건축 면적
치수 - 계산 높이: 1000 mm; 둘레: 95621.9 mm; 면적: 323.618 m2

# IfcSpace: 방화구획 31:7415175, 31
In: 지상 4층
LongName: 방화구획; InteriorOrExteriorSpace: INTERNAL; Group: 방화구획
Pset_SpaceCommon - Reference: 방화구획 31
BaseQuantities - NetFloorArea: 467.899 m2; Height: 4100 mm; GrossFloorArea: 467.899 m2; GrossVolume: 1918.39 m3
ID 데이터 - 번호: 31; 이름: 방화구획
구속조건 - 레벨: 지상 4층
기타 - 카테고리: 면적; 면적 양식 ID: 7408038; 면적 유형: 건축 면적
치수 - 계산 높이: 1000 mm; 둘레: 99658.1 mm; 면적: 467.899 m2

# IfcSpace: 방화구획 32:7415176, 32
In: 지상 4층
LongName: 방화구획; InteriorOrExteriorSpace: INTERNAL; Group: 방화구획
Pset_SpaceCommon - Reference: 방화구획 32
BaseQuantities - NetFloorArea: 166.666 m2; Height: 4100 mm; GrossFloorArea: 166.666 m2; GrossVolume: 683.332 m3
ID 데이터 - 번호: 32; 이름: 방화구획
구속조건 - 레벨: 지상 4층
기타 - 카테고리: 면적; 면적 양식 ID: 7408038; 면적 유형: 건축 면적
치수 - 계산 높이: 1000 mm; 둘레: 61308.7 mm; 면적: 166.666 m2

# IfcSpace: 방화구획 33:7415206, 33
In: 지상 5층
LongName: 방화구획; InteriorOrExteriorSpace: INTERNAL; Group: 방화구획
Pset_SpaceCommon - Reference: 방화구획 33
BaseQuantities - NetFloorArea: 217.635 m2; Height: 4100 mm; GrossFloorArea: 217.635 m2; GrossVolume: 892.305 m3
ID 데이터 - 번호: 33; 이름: 방화구획
구속조건 - 레벨: 지상 5층
기타 - 카테고리: 면적; 면적 양식 ID: 7408038; 면적 유형: 건축 면적
치수 - 계산 높이: 1000 mm; 둘레: 71752.6 mm; 면적: 217.635 m2

# IfcSpace: 방화구획 34:7415211, 34
In: 지상 5층
LongName: 방화구획; InteriorOrExteriorSpace: INTERNAL; Group: 방화구획
Pset_SpaceCommon - Reference: 방화구획 34
BaseQuantities - NetFloorArea: 323.619 m2; Height: 4100 mm; GrossFloorArea: 323.619 m2; GrossVolume: 1326.84 m3
ID 데이터 - 번호: 34; 이름: 방화구획
구속조건 - 레벨: 지상 5층
기타 - 카테고리: 면적; 면적 양식 ID: 7408038; 면적 유형: 건축 면적
치수 - 계산 높이: 1000 mm; 둘레: 95580.7 mm; 면적: 323.619 m2

# IfcSpace: 방화구획 35:7415212, 35
In: 지상 5층
LongName: 방화구획; InteriorOrExteriorSpace: INTERNAL; Group: 방화구획
Pset_SpaceCommon - Reference: 방화구획 35
BaseQuantities - NetFloorArea: 467.865 m2; Height: 4100 mm; GrossFloorArea: 467.865 m2; GrossVolume: 1918.24 m3
ID 데이터 - 번호: 35; 이름: 방화구획
구속조건 - 레벨: 지상 5층
기타 - 카테고리: 면적; 면적 양식 ID: 7408038; 면적 유형: 건축 면적
치수 - 계산 높이: 1000 mm; 둘레: 99584.4 mm; 면적: 467.865 m2

# IfcSpace: 방화구획 36:7415213, 36
In: 지상 5층
LongName: 방화구획; InteriorOrExteriorSpace: INTERNAL; Group: 방화구획
Pset_SpaceCommon - Reference: 방화구획 36
BaseQuantities - NetFloorArea: 166.666 m2; Height: 4100 mm; GrossFloorArea: 166.666 m2; GrossVolume: 683.332 m3
ID 데이터 - 번호: 36; 이름: 방화구획
구속조건 - 레벨: 지상 5층
기타 - 카테고리: 면적; 면적 양식 ID: 7408038; 면적 유형: 건축 면적
치수 - 계산 높이: 1000 mm; 둘레: 61308.7 mm; 면적: 166.666 m2

# IfcSpace: 방화구획 37:7415243, 37
In: 지상 6층
LongName: 방화구획; InteriorOrExteriorSpace: INTERNAL; Group: 방화구획
Pset_SpaceCommon - Reference: 방화구획 37
BaseQuantities - NetFloorArea: 217.635 m2; Height: 4100 mm; GrossFloorArea: 217.635 m2; GrossVolume: 892.305 m3
ID 데이터 - 번호: 37; 이름: 방화구획
구속조건 - 레벨: 지상 6층
기타 - 카테고리: 면적; 면적 양식 ID: 7408038; 면적 유형: 건축 면적
치수 - 계산 높이: 1000 mm; 둘레: 71752.6 mm; 면적: 217.635 m2

# IfcSpace: 방화구획 38:7415248, 38
In: 지상 6층
LongName: 방화구획; InteriorOrExteriorSpace: INTERNAL; Group: 방화구획
Pset_SpaceCommon - Reference: 방화구획 38
BaseQuantities - NetFloorArea: 323.618 m2; Height: 4100 mm; GrossFloorArea: 323.618 m2; GrossVolume: 1326.84 m3
ID 데이터 - 번호: 38; 이름: 방화구획
구속조건 - 레벨: 지상 6층
기타 - 카테고리: 면적; 면적 양식 ID: 7408038; 면적 유형: 건축 면적
치수 - 계산 높이: 1000 mm; 둘레: 95580.7 mm; 면적: 323.618 m2

# IfcSpace: 방화구획 39:7415249, 39
In: 지상 6층
LongName: 방화구획; InteriorOrExteriorSpace: INTERNAL; Group: 방화구획
Pset_SpaceCommon - Reference: 방화구획 39
BaseQuantities - NetFloorArea: 467.865 m2; Height: 4100 mm; GrossFloorArea: 467.865 m2; GrossVolume: 1918.24 m3
ID 데이터 - 번호: 39; 이름: 방화구획
구속조건 - 레벨: 지상 6층
기타 - 카테고리: 면적; 면적 양식 ID: 7408038; 면적 유형: 건축 면적
치수 - 계산 높이: 1000 mm; 둘레: 99584.4 mm; 면적: 467.865 m2

# IfcSpace: 방화구획 40:7415250, 40
In: 지상 6층
LongName: 방화구획; InteriorOrExteriorSpace: INTERNAL; Group: 방화구획
Pset_SpaceCommon - Reference: 방화구획 40
BaseQuantities - NetFloorArea: 166.666 m2; Height: 4100 mm; GrossFloorArea: 166.666 m2; GrossVolume: 683.332 m3
ID 데이터 - 번호: 40; 이름: 방화구획
구속조건 - 레벨: 지상 6층
기타 - 카테고리: 면적; 면적 양식 ID: 7408038; 면적 유형: 건축 면적
치수 - 계산 높이: 1000 mm; 둘레: 61308.7 mm; 면적: 166.666 m2

# IfcSpace: 방화구획 41:7415280, 41
In: 지상 7층
LongName: 방화구획; InteriorOrExteriorSpace: INTERNAL; Group: 방화구획
Pset_SpaceCommon - Reference: 방화구획 41
BaseQuantities - NetFloorArea: 217.635 m2; Height: 4100 mm; GrossFloorArea: 217.635 m2; GrossVolume: 892.305 m3
ID 데이터 - 번호: 41; 이름: 방화구획
구속조건 - 레벨: 지상 7층
기타 - 카테고리: 면적; 면적 양식 ID: 7408038; 면적 유형: 건축 면적
치수 - 계산 높이: 1000 mm; 둘레: 71752.6 mm; 면적: 217.635 m2

# IfcSpace: 방화구획 42:7415285, 42
In: 지상 7층
LongName: 방화구획; InteriorOrExteriorSpace: INTERNAL; Group: 방화구획
Pset_SpaceCommon - Reference: 방화구획 42
BaseQuantities - NetFloorArea: 323.618 m2; Height: 4100 mm; GrossFloorArea: 323.618 m2; GrossVolume: 1326.84 m3
ID 데이터 - 번호: 42; 이름: 방화구획
구속조건 - 레벨: 지상 7층
기타 - 카테고리: 면적; 면적 양식 ID: 7408038; 면적 유형: 건축 면적
치수 - 계산 높이: 1000 mm; 둘레: 95580.7 mm; 면적: 323.618 m2

# IfcSpace: 방화구획 43:7415286, 43
In: 지상 7층
LongName: 방화구획; InteriorOrExteriorSpace: INTERNAL; Group: 방화구획
Pset_SpaceCommon - Reference: 방화구획 43
BaseQuantities - NetFloorArea: 467.865 m2; Height: 4100 mm; GrossFloorArea: 467.865 m2; GrossVolume: 1918.24 m3
ID 데이터 - 번호: 43; 이름: 방화구획
구속조건 - 레벨: 지상 7층
기타 - 카테고리: 면적; 면적 양식 ID: 7408038; 면적 유형: 건축 면적
치수 - 계산 높이: 1000 mm; 둘레: 99584.4 mm; 면적: 467.865 m2

# IfcSpace: 방화구획 44:7415287, 44
In: 지상 7층
LongName: 방화구획; InteriorOrExteriorSpace: INTERNAL; Group: 방화구획
Pset_SpaceCommon - Reference: 방화구획 44
BaseQuantities - NetFloorArea: 166.666 m2; Height: 4100 mm; GrossFloorArea: 166.666 m2; GrossVolume: 683.332 m3
ID 데이터 - 번호: 44; 이름: 방화구획
구속조건 - 레벨: 지상 7층
기타 - 카테고리: 면적; 면적 양식 ID: 7408038; 면적 유형: 건축 면적
치수 - 계산 높이: 1000 mm; 둘레: 61308.7 mm; 면적: 166.666 m2

# IfcSpace: 방화구획 45:7415317, 45
In: 지상 8층
LongName: 방화구획; InteriorOrExteriorSpace: INTERNAL; Group: 방화구획
Pset_SpaceCommon - Reference: 방화구획 45
BaseQuantities - NetFloorArea: 217.635 m2; Height: 4100 mm; GrossFloorArea: 217.635 m2; GrossVolume: 892.305 m3
ID 데이터 - 번호: 45; 이름: 방화구획
구속조건 - 레벨: 지상 8층
기타 - 카테고리: 면적; 면적 양식 ID: 7408038; 면적 유형: 건축 면적
치수 - 계산 높이: 1000 mm; 둘레: 71752.6 mm; 면적: 217.635 m2

# IfcSpace: 방화구획 46:7415322, 46
In: 지상 8층
LongName: 방화구획; InteriorOrExteriorSpace: INTERNAL; Group: 방화구획
Pset_SpaceCommon - Reference: 방화구획 46
BaseQuantities - NetFloorArea: 323.618 m2; Height: 4100 mm; GrossFloorArea: 323.618 m2; GrossVolume: 1326.84 m3
ID 데이터 - 번호: 46; 이름: 방화구획
구속조건 - 레벨: 지상 8층
기타 - 카테고리: 면적; 면적 양식 ID: 7408038; 면적 유형: 건축 면적
치수 - 계산 높이: 1000 mm; 둘레: 95580.7 mm; 면적: 323.618 m2

# IfcSpace: 방화구획 47:7415323, 47
In: 지상 8층
LongName: 방화구획; InteriorOrExteriorSpace: INTERNAL; Group: 방화구획
Pset_SpaceCommon - Reference: 방화구획 47
BaseQuantities - NetFloorArea: 467.865 m2; Height: 4100 mm; GrossFloorArea: 467.865 m2; GrossVolume: 1918.24 m3
ID 데이터 - 번호: 47; 이름: 방화구획
구속조건 - 레벨: 지상 8층
기타 - 카테고리: 면적; 면적 양식 ID: 7408038; 면적 유형: 건축 면적
치수 - 계산 높이: 1000 mm; 둘레: 99584.4 mm; 면적: 467.865 m2

# IfcSpace: 방화구획 48:7415324, 48
In: 지상 8층
LongName: 방화구획; InteriorOrExteriorSpace: INTERNAL; Group: 방화구획
Pset_SpaceCommon - Reference: 방화구획 48
BaseQuantities - NetFloorArea: 166.666 m2; Height: 4100 mm; GrossFloorArea: 166.666 m2; GrossVolume: 683.332 m3
ID 데이터 - 번호: 48; 이름: 방화구획
구속조건 - 레벨: 지상 8층
기타 - 카테고리: 면적; 면적 양식 ID: 7408038; 면적 유형: 건축 면적
치수 - 계산 높이: 1000 mm; 둘레: 61308.7 mm; 면적: 166.666 m2

# IfcSpace: 방화구획 49:7415354, 49
In: 지상 9층
LongName: 방화구획; InteriorOrExteriorSpace: INTERNAL; Group: 방화구획
Pset_SpaceCommon - Reference: 방화구획 49
BaseQuantities - NetFloorArea: 217.635 m2; Height: 4500 mm; GrossFloorArea: 217.635 m2; GrossVolume: 979.359 m3
ID 데이터 - 번호: 49; 이름: 방화구획
구속조건 - 레벨: 지상 9층
기타 - 카테고리: 면적; 면적 양식 ID: 7408038; 면적 유형: 건축 면적
치수 - 계산 높이: 1000 mm; 둘레: 71752.6 mm; 면적: 217.635 m2

# IfcSpace: 방화구획 50:7415359, 50
In: 지상 9층
LongName: 방화구획; InteriorOrExteriorSpace: INTERNAL; Group: 방화구획
Pset_SpaceCommon - Reference: 방화구획 50
BaseQuantities - NetFloorArea: 323.618 m2; Height: 4500 mm; GrossFloorArea: 323.618 m2; GrossVolume: 1456.28 m3
ID 데이터 - 번호: 50; 이름: 방화구획
구속조건 - 레벨: 지상 9층
기타 - 카테고리: 면적; 면적 양식 ID: 7408038; 면적 유형: 건축 면적
치수 - 계산 높이: 1000 mm; 둘레: 95580.7 mm; 면적: 323.618 m2

# IfcSpace: 방화구획 51:7415360, 51
In: 지상 9층
LongName: 방화구획; InteriorOrExteriorSpace: INTERNAL; Group: 방화구획
Pset_SpaceCommon - Reference: 방화구획 51
BaseQuantities - NetFloorArea: 467.865 m2; Height: 4500 mm; GrossFloorArea: 467.865 m2; GrossVolume: 2105.39 m3
ID 데이터 - 번호: 51; 이름: 방화구획
구속조건 - 레벨: 지상 9층
기타 - 카테고리: 면적; 면적 양식 ID: 7408038; 면적 유형: 건축 면적
치수 - 계산 높이: 1000 mm; 둘레: 99584.4 mm; 면적: 467.865 m2

# IfcSpace: 방화구획 52:7415361, 52
In: 지상 9층
LongName: 방화구획; InteriorOrExteriorSpace: INTERNAL; Group: 방화구획
Pset_SpaceCommon - Reference: 방화구획 52
BaseQuantities - NetFloorArea: 166.666 m2; Height: 4500 mm; GrossFloorArea: 166.666 m2; GrossVolume: 749.999 m3
ID 데이터 - 번호: 52; 이름: 방화구획
구속조건 - 레벨: 지상 9층
기타 - 카테고리: 면적; 면적 양식 ID: 7408038; 면적 유형: 건축 면적
치수 - 계산 높이: 1000 mm; 둘레: 61308.7 mm; 면적: 166.666 m2

# IfcSpace: 방화구획 53:7415391, 53
In: 지상 10층
LongName: 방화구획; InteriorOrExteriorSpace: INTERNAL; Group: 방화구획
Pset_SpaceCommon - Reference: 방화구획 53
BaseQuantities - NetFloorArea: 217.529 m2; Height: 5000 mm; GrossFloorArea: 217.529 m2; GrossVolume: 1087.65 m3
ID 데이터 - 번호: 53; 이름: 방화구획
구속조건 - 레벨: 지상 10층
기타 - 카테고리: 면적; 면적 양식 ID: 7408038; 면적 유형: 건축 면적
치수 - 계산 높이: 1000 mm; 둘레: 71752.6 mm; 면적: 217.529 m2

# IfcSpace: 방화구획 54:7415396, 54
In: 지상 10층
LongName: 방화구획; InteriorOrExteriorSpace: INTERNAL; Group: 방화구획
Pset_SpaceCommon - Reference: 방화구획 54
BaseQuantities - NetFloorArea: 323.605 m2; Height: 5000 mm; GrossFloorArea: 323.605 m2; GrossVolume: 1618.02 m3
ID 데이터 - 번호: 54; 이름: 방화구획
구속조건 - 레벨: 지상 10층
기타 - 카테고리: 면적; 면적 양식 ID: 7408038; 면적 유형: 건축 면적
치수 - 계산 높이: 1000 mm; 둘레: 95580 mm; 면적: 323.605 m2

# IfcSpace: 방화구획 55:7415397, 55
In: 지상 10층
LongName: 방화구획; InteriorOrExteriorSpace: INTERNAL; Group: 방화구획
Pset_SpaceCommon - Reference: 방화구획 55
BaseQuantities - NetFloorArea: 467.857 m2; Height: 5000 mm; GrossFloorArea: 467.857 m2; GrossVolume: 2339.28 m3
ID 데이터 - 번호: 55; 이름: 방화구획
구속조건 - 레벨: 지상 10층
기타 - 카테고리: 면적; 면적 양식 ID: 7408038; 면적 유형: 건축 면적
치수 - 계산 높이: 1000 mm; 둘레: 99583.8 mm; 면적: 467.857 m2

# IfcSpace: 방화구획 56:7415398, 56
In: 지상 10층
LongName: 방화구획; InteriorOrExteriorSpace: INTERNAL; Group: 방화구획
Pset_SpaceCommon - Reference: 방화구획 56
BaseQuantities - NetFloorArea: 165.224 m2; Height: 5000 mm; GrossFloorArea: 165.224 m2; GrossVolume: 826.122 m3
ID 데이터 - 번호: 56; 이름: 방화구획
구속조건 - 레벨: 지상 10층
기타 - 카테고리: 면적; 면적 양식 ID: 7408038; 면적 유형: 건축 면적
치수 - 계산 높이: 1000 mm; 둘레: 60908.7 mm; 면적: 165.224 m2

# IfcSpace: 방화구획 57:7415936, 57
In: 지하1층
LongName: 방화구획; InteriorOrExteriorSpace: INTERNAL; Group: 방화구획
Pset_SpaceCommon - Reference: 방화구획 57
BaseQuantities - NetFloorArea: 157.95 m2; Height: 6100 mm; GrossFloorArea: 157.95 m2; GrossVolume: 963.495 m3
ID 데이터 - 번호: 57; 이름: 방화구획
구속조건 - 레벨: 지하1층
기타 - 카테고리: 면적; 면적 양식 ID: 7408038; 면적 유형: 건축 면적
치수 - 계산 높이: 0 mm; 둘레: 50400 mm; 면적: 157.95 m2

# IfcSpace: 방화구획 58:7415938, 58
In: 지하1층
LongName: 방화구획; InteriorOrExteriorSpace: INTERNAL; Group: 방화구획
Pset_SpaceCommon - Reference: 방화구획 58
BaseQuantities - NetFloorArea: 180.9 m2; Height: 6100 mm; GrossFloorArea: 180.9 m2; GrossVolume: 1103.49 m3
ID 데이터 - 번호: 58; 이름: 방화구획
구속조건 - 레벨: 지하1층
기타 - 카테고리: 면적; 면적 양식 ID: 7408038; 면적 유형: 건축 면적
치수 - 계산 높이: 0 mm; 둘레: 53800 mm; 면적: 180.9 m2

# IfcSpace: 방화구획 59:7415940, 59
In: 지하1층
LongName: 방화구획; InteriorOrExteriorSpace: INTERNAL; Group: 방화구획
Pset_SpaceCommon - Reference: 방화구획 59
BaseQuantities - NetFloorArea: 218.603 m2; Height: 6100 mm; GrossFloorArea: 218.603 m2; GrossVolume: 1333.48 m3
ID 데이터 - 번호: 59; 이름: 방화구획
구속조건 - 레벨: 지하1층
기타 - 카테고리: 면적; 면적 양식 ID: 7408038; 면적 유형: 건축 면적
치수 - 계산 높이: 0 mm; 둘레: 58953.1 mm; 면적: 218.603 m2

# IfcSpace: 방화구획 60:7415942, 60
In: 지하1층
LongName: 방화구획; InteriorOrExteriorSpace: INTERNAL; Group: 방화구획
Pset_SpaceCommon - Reference: 방화구획 60
BaseQuantities - NetFloorArea: 206.687 m2; Height: 6100 mm; GrossFloorArea: 206.687 m2; GrossVolume: 1260.79 m3
ID 데이터 - 번호: 60; 이름: 방화구획
구속조건 - 레벨: 지하1층
기타 - 카테고리: 면적; 면적 양식 ID: 7408038; 면적 유형: 건축 면적
치수 - 계산 높이: 0 mm; 둘레: 58147.7 mm; 면적: 206.687 m2

# IfcSpace: 방화구획 61:7415944, 61
In: 지하1층
LongName: 방화구획; InteriorOrExteriorSpace: INTERNAL; Group: 방화구획
Pset_SpaceCommon - Reference: 방화구획 61
BaseQuantities - NetFloorArea: 196.98 m2; Height: 6100 mm; GrossFloorArea: 196.98 m2; GrossVolume: 1201.58 m3
ID 데이터 - 번호: 61; 이름: 방화구획
구속조건 - 레벨: 지하1층
기타 - 카테고리: 면적; 면적 양식 ID: 7408038; 면적 유형: 건축 면적
치수 - 계산 높이: 0 mm; 둘레: 56200 mm; 면적: 196.98 m2

# IfcSpace: 방화구획 62:7415946, 62
In: 지하1층
LongName: 방화구획; InteriorOrExteriorSpace: INTERNAL; Group: 방화구획
Pset_SpaceCommon - Reference: 방화구획 62
BaseQuantities - NetFloorArea: 171.99 m2; Height: 6100 mm; GrossFloorArea: 171.99 m2; GrossVolume: 1049.14 m3
ID 데이터 - 번호: 62; 이름: 방화구획
구속조건 - 레벨: 지하1층
기타 - 카테고리: 면적; 면적 양식 ID: 7408038; 면적 유형: 건축 면적
치수 - 계산 높이: 0 mm; 둘레: 52800 mm; 면적: 171.99 m2

# IfcSpace: 방화구획 63:7415948, 63
In: 지하1층
LongName: 방화구획; InteriorOrExteriorSpace: INTERNAL; Group: 방화구획
Pset_SpaceCommon - Reference: 방화구획 63
BaseQuantities - NetFloorArea: 90.09 m2; Height: 6100 mm; GrossFloorArea: 90.09 m2; GrossVolume: 549.549 m3
ID 데이터 - 번호: 63; 이름: 방화구획
구속조건 - 레벨: 지하1층
기타 - 카테고리: 면적; 면적 양식 ID: 7408038; 면적 유형: 건축 면적
치수 - 계산 높이: 0 mm; 둘레: 38800 mm; 면적: 90.09 m2

# IfcSpace: 방화구획 64:7415950, 64
In: 지하1층
LongName: 방화구획; InteriorOrExteriorSpace: INTERNAL; Group: 방화구획
Pset_SpaceCommon - Reference: 방화구획 64
BaseQuantities - NetFloorArea: 103.18 m2; Height: 6100 mm; GrossFloorArea: 103.18 m2; GrossVolume: 629.398 m3
ID 데이터 - 번호: 64; 이름: 방화구획
구속조건 - 레벨: 지하1층
기타 - 카테고리: 면적; 면적 양식 ID: 7408038; 면적 유형: 건축 면적
치수 - 계산 높이: 0 mm; 둘레: 42200 mm; 면적: 103.18 m2

# IfcSpace: 방화구획 65:7415952, 65
In: 지하1층
LongName: 방화구획; InteriorOrExteriorSpace: INTERNAL; Group: 방화구획
Pset_SpaceCommon - Reference: 방화구획 65
BaseQuantities - NetFloorArea: 107.8 m2; Height: 6100 mm; GrossFloorArea: 107.8 m2; GrossVolume: 657.58 m3
ID 데이터 - 번호: 65; 이름: 방화구획
구속조건 - 레벨: 지하1층
기타 - 카테고리: 면적; 면적 양식 ID: 7408038; 면적 유형: 건축 면적
치수 - 계산 높이: 0 mm; 둘레: 43400 mm; 면적: 107.8 m2

# IfcSpace: 방화구획 75:7416238, 75
In: 지하2층
LongName: 방화구획; InteriorOrExteriorSpace: INTERNAL; Group: 방화구획
Pset_SpaceCommon - Reference: 방화구획 75
BaseQuantities - NetFloorArea: 157.95 m2; Height: 4000 mm; GrossFloorArea: 157.95 m2; GrossVolume: 631.8 m3
ID 데이터 - 번호: 75; 이름: 방화구획
구속조건 - 레벨: 지하2층
기타 - 카테고리: 면적; 면적 양식 ID: 7408038; 면적 유형: 건축 면적
치수 - 계산 높이: 0 mm; 둘레: 50400 mm; 면적: 157.95 m2

# IfcSpace: 방화구획 76:7416239, 76
In: 지하2층
LongName: 방화구획; InteriorOrExteriorSpace: INTERNAL; Group: 방화구획
Pset_SpaceCommon - Reference: 방화구획 76
BaseQuantities - NetFloorArea: 180.9 m2; Height: 4000 mm; GrossFloorArea: 180.9 m2; GrossVolume: 723.6 m3
ID 데이터 - 번호: 76; 이름: 방화구획
구속조건 - 레벨: 지하2층
기타 - 카테고리: 면적; 면적 양식 ID: 7408038; 면적 유형: 건축 면적
치수 - 계산 높이: 0 mm; 둘레: 53800 mm; 면적: 180.9 m2

# IfcSpace: 방화구획 77:7416240, 77
In: 지하2층
LongName: 방화구획; InteriorOrExteriorSpace: INTERNAL; Group: 방화구획
Pset_SpaceCommon - Reference: 방화구획 77
BaseQuantities - NetFloorArea: 218.603 m2; Height: 4000 mm; GrossFloorArea: 218.603 m2; GrossVolume: 874.411 m3
ID 데이터 - 번호: 77; 이름: 방화구획
구속조건 - 레벨: 지하2층
기타 - 카테고리: 면적; 면적 양식 ID: 7408038; 면적 유형: 건축 면적
치수 - 계산 높이: 0 mm; 둘레: 58953.1 mm; 면적: 218.603 m2

# IfcSpace: 방화구획 78:7416241, 78
In: 지하2층
LongName: 방화구획; InteriorOrExteriorSpace: INTERNAL; Group: 방화구획
Pset_SpaceCommon - Reference: 방화구획 78
BaseQuantities - NetFloorArea: 206.687 m2; Height: 4000 mm; GrossFloorArea: 206.687 m2; GrossVolume: 826.746 m3
ID 데이터 - 번호: 78; 이름: 방화구획
구속조건 - 레벨: 지하2층
기타 - 카테고리: 면적; 면적 양식 ID: 7408038; 면적 유형: 건축 면적
치수 - 계산 높이: 0 mm; 둘레: 58147.7 mm; 면적: 206.687 m2

# IfcSpace: 방화구획 79:7416242, 79
In: 지하2층
LongName: 방화구획; InteriorOrExteriorSpace: INTERNAL; Group: 방화구획
Pset_SpaceCommon - Reference: 방화구획 79
BaseQuantities - NetFloorArea: 196.98 m2; Height: 4000 mm; GrossFloorArea: 196.98 m2; GrossVolume: 787.92 m3
ID 데이터 - 번호: 79; 이름: 방화구획
구속조건 - 레벨: 지하2층
기타 - 카테고리: 면적; 면적 양식 ID: 7408038; 면적 유형: 건축 면적
치수 - 계산 높이: 0 mm; 둘레: 56200 mm; 면적: 196.98 m2

# IfcSpace: 방화구획 80:7416243, 80
In: 지하2층
LongName: 방화구획; InteriorOrExteriorSpace: INTERNAL; Group: 방화구획
Pset_SpaceCommon - Reference: 방화구획 80
BaseQuantities - NetFloorArea: 171.99 m2; Height: 4000 mm; GrossFloorArea: 171.99 m2; GrossVolume: 687.96 m3
ID 데이터 - 번호: 80; 이름: 방화구획
구속조건 - 레벨: 지하2층
기타 - 카테고리: 면적; 면적 양식 ID: 7408038; 면적 유형: 건축 면적
치수 - 계산 높이: 0 mm; 둘레: 52800 mm; 면적: 171.99 m2

# IfcSpace: 방화구획 81:7416244, 81
In: 지하2층
LongName: 방화구획; InteriorOrExteriorSpace: INTERNAL; Group: 방화구획
Pset_SpaceCommon - Reference: 방화구획 81
BaseQuantities - NetFloorArea: 90.0896 m2; Height: 4000 mm; GrossFloorArea: 90.0896 m2; GrossVolume: 360.358 m3
ID 데이터 - 번호: 81; 이름: 방화구획
구속조건 - 레벨: 지하2층
기타 - 카테고리: 면적; 면적 양식 ID: 7408038; 면적 유형: 건축 면적
치수 - 계산 높이: 0 mm; 둘레: 38799.9 mm; 면적: 90.0896 m2

# IfcSpace: 방화구획 82:7416245, 82
In: 지하2층
LongName: 방화구획; InteriorOrExteriorSpace: INTERNAL; Group: 방화구획
Pset_SpaceCommon - Reference: 방화구획 82
BaseQuantities - NetFloorArea: 103.179 m2; Height: 4000 mm; GrossFloorArea: 103.179 m2; GrossVolume: 412.718 m3
ID 데이터 - 번호: 82; 이름: 방화구획
구속조건 - 레벨: 지하2층
기타 - 카테고리: 면적; 면적 양식 ID: 7408038; 면적 유형: 건축 면적
치수 - 계산 높이: 0 mm; 둘레: 42199.9 mm; 면적: 103.179 m2

# IfcSpace: 방화구획 83:7416246, 83
In: 지하2층
LongName: 방화구획; InteriorOrExteriorSpace: INTERNAL; Group: 방화구획
Pset_SpaceCommon - Reference: 방화구획 83
BaseQuantities - NetFloorArea: 107.15 m2; Height: 4000 mm; GrossFloorArea: 107.15 m2; GrossVolume: 428.598 m3
ID 데이터 - 번호: 83; 이름: 방화구획
구속조건 - 레벨: 지하2층
기타 - 카테고리: 면적; 면적 양식 ID: 7408038; 면적 유형: 건축 면적
치수 - 계산 높이: 0 mm; 둘레: 43599.9 mm; 면적: 107.15 m2

# IfcSpace: 복도 166:3691265, 166
In: 지상 1층
LongName: 복도; InteriorOrExteriorSpace: INTERNAL
Pset_SpaceCommon - Reference: 복도 166; FloorCovering: T30 화강석 물갈기; WallCovering: 수성페인트; CeilingCovering: T6무석면택스마감
BaseQuantities - NetFloorArea: 190.227 m2; Height: 4180 mm; GrossFloorArea: 190.227 m2; GrossVolume: 795.151 m3
ID 데이터 - 바닥 마감: T30 화강석 물갈기; 번호: 166; 베이스 마감: 목재 걸레받이; 벽 마감: 수성페인트; 이름: 복도; 천장 마감: T6무석면택스마감
공정 - 공정: 새 구성
구속조건 - 상한값: 지상 1층; 레벨: 지상 1층; 베이스 간격띄우기: -550 mm; 한계 간격띄우기: 3630 mm
기타 - 거실여부: no; 공정 ID: 0; 카테고리: 룸; 방화구획: yes; 공간분류코드: 33105; 실ID: 118
에너지 해석 - 구역별 실제 전력 부하: 0; 구역별 실제 조명 부하: 0; 기초 전력 부하: 공간 유형별; 기초 조명 부하: 공간 유형별; 사람 수: 0; 열 부하 값: 공간 유형별; 전력 부하 단위: 전력 밀도; 조명 부하 단위: 전력 밀도; 1인당 잠열 취득: 58.6142 W; 1인당 현열 취득: 73.2678 W; 개인별 면적: 28.5714 m2; 실제 전력 부하: 0 W; 실제 조명 부하: 0 W; 지정된 구역별 전력 부하: 13.9931; 지정된 구역별 조명 부하: 10.7639; 지정된 전력 부하: 0 W; 지정된 조명 부하: 0 W; 천장속 조명 방사: 20; 총 개인별 열 취득: 131.882 W
치수 - 계산 높이: 1000 mm; 둘레: 136366 mm; 면적: 190.227 m2; 무한한 높이: 4180 mm; 체적: 705.576 m3

# IfcSpace: 복도 190:3691573, 190
In: 지상 2층
LongName: 복도; InteriorOrExteriorSpace: INTERNAL
Pset_SpaceCommon - Reference: 복도 190; FloorCovering: T30 화강석 물갈기; WallCovering: 수성페인트; CeilingCovering: T6무석면택스마감
BaseQuantities - NetFloorArea: 96.3288 m2; Height: 3080 mm; GrossPerimeter: 89573.8 mm; GrossFloorArea: 96.3288 m2; GrossVolume: 296.693 m3
ID 데이터 - 바닥 마감: T30 화강석 물갈기; 번호: 190; 베이스 마감: 목재 걸레받이; 벽 마감: 수성페인트; 이름: 복도; 천장 마감: T6무석면택스마감
공정 - 공정: 새 구성
구속조건 - 베이스 간격띄우기: 0 mm; 상한값: 지상 2층; 레벨: 지상 2층; 한계 간격띄우기: 3080 mm
기타 - 거실여부: no; 공정 ID: 0; 카테고리: 룸; 방화구획: yes; 공간분류코드: 33105; 실ID: 212
에너지 해석 - 구역별 실제 전력 부하: 0; 구역별 실제 조명 부하: 0; 기초 전력 부하: 공간 유형별; 기초 조명 부하: 공간 유형별; 사람 수: 0; 열 부하 값: 공간 유형별; 전력 부하 단위: 전력 밀도; 조명 부하 단위: 전력 밀도; 1인당 잠열 취득: 58.6142 W; 1인당 현열 취득: 73.2678 W; 개인별 면적: 28.5714 m2; 실제 전력 부하: 0 W; 실제 조명 부하: 0 W; 지정된 구역별 전력 부하: 13.9931; 지정된 구역별 조명 부하: 10.7639; 지정된 전력 부하: 0 W; 지정된 조명 부하: 0 W; 천장속 조명 방사: 20; 총 개인별 열 취득: 131.882 W
치수 - 계산 높이: 1000 mm; 둘레: 89573.8 mm; 면적: 96.3288 m2; 무한한 높이: 3080 mm; 체적: 296.693 m3

# IfcSpace: 복도 204:3691798, 204
In: 지상 3층
LongName: 복도; InteriorOrExteriorSpace: INTERNAL
Pset_SpaceCommon - Reference: 복도 204; FloorCovering: T30 화강석 물갈기; WallCovering: 수성페인트; CeilingCovering: T6무석면택스마감
BaseQuantities - NetFloorArea: 95.8139 m2; Height: 2680 mm; GrossPerimeter: 89517.3 mm; GrossFloorArea: 95.8139 m2; GrossVolume: 256.781 m3
ID 데이터 - 바닥 마감: T30 화강석 물갈기; 번호: 204; 베이스 마감: 목재 걸레받이; 벽 마감: 수성페인트; 이름: 복도; 천장 마감: T6무석면택스마감
공정 - 공정: 새 구성
구속조건 - 베이스 간격띄우기: 0 mm; 상한값: 지상 3층; 레벨: 지상 3층; 한계 간격띄우기: 2680 mm
기타 - 거실여부: no; 공정 ID: 0; 카테고리: 룸; 방화구획: yes; 공간분류코드: 33105; 실ID: 313
에너지 해석 - 구역별 실제 전력 부하: 0; 구역별 실제 조명 부하: 0; 기초 전력 부하: 공간 유형별; 기초 조명 부하: 공간 유형별; 사람 수: 0; 열 부하 값: 공간 유형별; 전력 부하 단위: 전력 밀도; 조명 부하 단위: 전력 밀도; 1인당 잠열 취득: 58.6142 W; 1인당 현열 취득: 73.2678 W; 개인별 면적: 28.5714 m2; 실제 전력 부하: 0 W; 실제 조명 부하: 0 W; 지정된 구역별 전력 부하: 13.9931; 지정된 구역별 조명 부하: 10.7639; 지정된 전력 부하: 0 W; 지정된 조명 부하: 0 W; 천장속 조명 방사: 20; 총 개인별 열 취득: 131.882 W
치수 - 계산 높이: 1000 mm; 둘레: 89355.3 mm; 면적: 95.8139 m2; 무한한 높이: 2680 mm; 체적: 256.781 m3

# IfcSpace: 복도 216:3692725, 216
In: 지상 4층
LongName: 복도; InteriorOrExteriorSpace: INTERNAL
Pset_SpaceCommon - Reference: 복도 216; FloorCovering: T30 화강석 물갈기; WallCovering: 수성페인트; CeilingCovering: T6무석면택스마감
BaseQuantities - NetFloorArea: 89.6699 m2; Height: 2680 mm; GrossPerimeter: 84581.6 mm; GrossFloorArea: 89.6699 m2; GrossVolume: 240.315 m3
ID 데이터 - 바닥 마감: T30 화강석 물갈기; 번호: 216; 베이스 마감: 목재 걸레받이; 벽 마감: 수성페인트; 이름: 복도; 천장 마감: T6무석면택스마감
공정 - 공정: 새 구성
구속조건 - 베이스 간격띄우기: 0 mm; 상한값: 지상 4층; 레벨: 지상 4층; 한계 간격띄우기: 2680 mm
기타 - 거실여부: no; 공정 ID: 0; 카테고리: 룸; 방화구획: yes; 공간분류코드: 33105; 실ID: 407
에너지 해석 - 구역별 실제 전력 부하: 0; 구역별 실제 조명 부하: 0; 기초 전력 부하: 공간 유형별; 기초 조명 부하: 공간 유형별; 사람 수: 0; 열 부하 값: 공간 유형별; 전력 부하 단위: 전력 밀도; 조명 부하 단위: 전력 밀도; 1인당 잠열 취득: 58.6142 W; 1인당 현열 취득: 73.2678 W; 개인별 면적: 28.5714 m2; 실제 전력 부하: 0 W; 실제 조명 부하: 0 W; 지정된 구역별 전력 부하: 13.9931; 지정된 구역별 조명 부하: 10.7639; 지정된 전력 부하: 0 W; 지정된 조명 부하: 0 W; 천장속 조명 방사: 20; 총 개인별 열 취득: 131.882 W
치수 - 계산 높이: 1000 mm; 둘레: 84581.6 mm; 면적: 89.6699 m2; 무한한 높이: 2680 mm; 체적: 240.315 m3

# IfcSpace: 복도 236:3692964, 236
In: 지상 5층
LongName: 복도; InteriorOrExteriorSpace: INTERNAL
Pset_SpaceCommon - Reference: 복도 236; FloorCovering: T30 화강석 물갈기; WallCovering: 수성페인트; CeilingCovering: T6무석면택스마감
BaseQuantities - NetFloorArea: 89.6597 m2; Height: 2680 mm; GrossPerimeter: 84419.9 mm; GrossFloorArea: 89.6597 m2; GrossVolume: 240.288 m3
ID 데이터 - 바닥 마감: T30 화강석 물갈기; 번호: 236; 베이스 마감: 목재 걸레받이; 벽 마감: 수성페인트; 이름: 복도; 천장 마감: T6무석면택스마감
공정 - 공정: 새 구성
구속조건 - 베이스 간격띄우기: 0 mm; 상한값: 지상 5층; 레벨: 지상 5층; 한계 간격띄우기: 2680 mm
기타 - 거실여부: no; 공정 ID: 0; 카테고리: 룸; 방화구획: yes; 공간분류코드: 33105; 실ID: 513
에너지 해석 - 구역별 실제 전력 부하: 0; 구역별 실제 조명 부하: 0; 기초 전력 부하: 공간 유형별; 기초 조명 부하: 공간 유형별; 사람 수: 0; 열 부하 값: 공간 유형별; 전력 부하 단위: 전력 밀도; 조명 부하 단위: 전력 밀도; 1인당 잠열 취득: 58.6142 W; 1인당 현열 취득: 73.2678 W; 개인별 면적: 28.5714 m2; 실제 전력 부하: 0 W; 실제 조명 부하: 0 W; 지정된 구역별 전력 부하: 13.9931; 지정된 구역별 조명 부하: 10.7639; 지정된 전력 부하: 0 W; 지정된 조명 부하: 0 W; 천장속 조명 방사: 20; 총 개인별 열 취득: 131.882 W
치수 - 계산 높이: 1000 mm; 둘레: 84419.9 mm; 면적: 89.6597 m2; 무한한 높이: 2680 mm; 체적: 240.288 m3

# IfcSpace: 복도 251:3694145, 251
In: 지상 6층
LongName: 복도; InteriorOrExteriorSpace: INTERNAL
Pset_SpaceCommon - Reference: 복도 251; FloorCovering: T30 화강석 물갈기; WallCovering: 수성페인트; CeilingCovering: T6무석면택스마감
BaseQuantities - NetFloorArea: 89.6469 m2; Height: 2680 mm; GrossPerimeter: 84589.9 mm; GrossFloorArea: 89.6469 m2; GrossVolume: 240.254 m3
ID 데이터 - 바닥 마감: T30 화강석 물갈기; 번호: 251; 베이스 마감: 목재 걸레받이; 벽 마감: 수성페인트; 이름: 복도; 천장 마감: T6무석면택스마감
공정 - 공정: 새 구성
구속조건 - 베이스 간격띄우기: 0 mm; 상한값: 지상 6층; 레벨: 지상 6층; 한계 간격띄우기: 2680 mm
기타 - 거실여부: no; 공정 ID: 0; 카테고리: 룸; 방화구획: yes; 공간분류코드: 33105; 실ID: 613
에너지 해석 - 구역별 실제 전력 부하: 0; 구역별 실제 조명 부하: 0; 기초 전력 부하: 공간 유형별; 기초 조명 부하: 공간 유형별; 사람 수: 0; 열 부하 값: 공간 유형별; 전력 부하 단위: 전력 밀도; 조명 부하 단위: 전력 밀도; 1인당 잠열 취득: 58.6142 W; 1인당 현열 취득: 73.2678 W; 개인별 면적: 28.5714 m2; 실제 전력 부하: 0 W; 실제 조명 부하: 0 W; 지정된 구역별 전력 부하: 13.9931; 지정된 구역별 조명 부하: 10.7639; 지정된 전력 부하: 0 W; 지정된 조명 부하: 0 W; 천장속 조명 방사: 20; 총 개인별 열 취득: 131.882 W
치수 - 계산 높이: 1000 mm; 둘레: 84589.9 mm; 면적: 89.6469 m2; 무한한 높이: 2680 mm; 체적: 240.254 m3

# IfcSpace: 복도 268:3694370, 268
In: 지상 7층
LongName: 복도; InteriorOrExteriorSpace: INTERNAL
Pset_SpaceCommon - Reference: 복도 268; FloorCovering: T30 화강석 물갈기; WallCovering: 수성페인트; CeilingCovering: T6무석면택스마감
BaseQuantities - NetFloorArea: 89.6462 m2; Height: 2438.4 mm; GrossPerimeter: 84409.9 mm; GrossFloorArea: 89.6462 m2; GrossVolume: 218.593 m3
ID 데이터 - 바닥 마감: T30 화강석 물갈기; 번호: 268; 베이스 마감: 목재 걸레받이; 벽 마감: 수성페인트; 이름: 복도; 천장 마감: T6무석면택스마감
공정 - 공정: 새 구성
구속조건 - 베이스 간격띄우기: 0 mm; 한계 간격띄우기: 2438.4 mm; 상한값: 지상 7층; 레벨: 지상 7층
기타 - 거실여부: no; 공정 ID: 0; 카테고리: 룸; 공간분류코드: 33105; 실ID: 713
에너지 해석 - 구역별 실제 전력 부하: 0; 구역별 실제 조명 부하: 0; 기초 전력 부하: 공간 유형별; 기초 조명 부하: 공간 유형별; 사람 수: 0; 열 부하 값: 공간 유형별; 전력 부하 단위: 전력 밀도; 조명 부하 단위: 전력 밀도; 1인당 잠열 취득: 58.6142 W; 1인당 현열 취득: 73.2678 W; 개인별 면적: 28.5714 m2; 실제 전력 부하: 0 W; 실제 조명 부하: 0 W; 지정된 구역별 전력 부하: 13.9931; 지정된 구역별 조명 부하: 10.7639; 지정된 전력 부하: 0 W; 지정된 조명 부하: 0 W; 천장속 조명 방사: 20; 총 개인별 열 취득: 131.882 W
치수 - 무한한 높이: 2438.4 mm; 계산 높이: 1000 mm; 둘레: 84409.9 mm; 면적: 89.6462 m2; 체적: 218.593 m3

# IfcSpace: 복도 283:3694587, 283
In: 지상 8층
LongName: 복도; InteriorOrExteriorSpace: INTERNAL
Pset_SpaceCommon - Reference: 복도 283; FloorCovering: T30 화강석 물갈기; WallCovering: 수성페인트; CeilingCovering: T6무석면택스마감
BaseQuantities - NetFloorArea: 89.654 m2; Height: 2680 mm; GrossPerimeter: 84499.9 mm; GrossFloorArea: 89.654 m2; GrossVolume: 240.273 m3
ID 데이터 - 바닥 마감: T30 화강석 물갈기; 번호: 283; 베이스 마감: 목재 걸레받이; 벽 마감: 수성페인트; 이름: 복도; 천장 마감: T6무석면택스마감
공정 - 공정: 새 구성
구속조건 - 베이스 간격띄우기: 0 mm; 상한값: 지상 8층; 레벨: 지상 8층; 한계 간격띄우기: 2680 mm
기타 - 거실여부: no; 공정 ID: 0; 카테고리: 룸; 공간분류코드: 33105; 실ID: 810
에너지 해석 - 구역별 실제 전력 부하: 0; 구역별 실제 조명 부하: 0; 기초 전력 부하: 공간 유형별; 기초 조명 부하: 공간 유형별; 사람 수: 0; 열 부하 값: 공간 유형별; 전력 부하 단위: 전력 밀도; 조명 부하 단위: 전력 밀도; 1인당 잠열 취득: 58.6142 W; 1인당 현열 취득: 73.2678 W; 개인별 면적: 28.5714 m2; 실제 전력 부하: 0 W; 실제 조명 부하: 0 W; 지정된 구역별 전력 부하: 13.9931; 지정된 구역별 조명 부하: 10.7639; 지정된 전력 부하: 0 W; 지정된 조명 부하: 0 W; 천장속 조명 방사: 20; 총 개인별 열 취득: 131.882 W
치수 - 계산 높이: 1000 mm; 둘레: 84499.9 mm; 면적: 89.654 m2; 무한한 높이: 2680 mm; 체적: 240.273 m3

# IfcSpace: 복도 294:3694741, 294
In: 지상 9층
LongName: 복도; InteriorOrExteriorSpace: INTERNAL
Pset_SpaceCommon - Reference: 복도 294; FloorCovering: T30 화강석 물갈기; WallCovering: 수성페인트; CeilingCovering: T6무석면택스마감
BaseQuantities - NetFloorArea: 96.6244 m2; Height: 3080 mm; GrossPerimeter: 89909.9 mm; GrossFloorArea: 96.6244 m2; GrossVolume: 297.603 m3
ID 데이터 - 바닥 마감: T30 화강석 물갈기; 번호: 294; 베이스 마감: 목재 걸레받이; 벽 마감: 수성페인트; 이름: 복도; 천장 마감: T6무석면택스마감
공정 - 공정: 새 구성
구속조건 - 베이스 간격띄우기: 0 mm; 상한값: 지상 9층; 레벨: 지상 9층; 한계 간격띄우기: 3080 mm
기타 - 거실여부: no; 공정 ID: 0; 카테고리: 룸; 공간분류코드: 33105; 실ID: 905
에너지 해석 - 구역별 실제 전력 부하: 0; 구역별 실제 조명 부하: 0; 기초 전력 부하: 공간 유형별; 기초 조명 부하: 공간 유형별; 사람 수: 0; 열 부하 값: 공간 유형별; 전력 부하 단위: 전력 밀도; 조명 부하 단위: 전력 밀도; 1인당 잠열 취득: 58.6142 W; 1인당 현열 취득: 73.2678 W; 개인별 면적: 28.5714 m2; 실제 전력 부하: 0 W; 실제 조명 부하: 0 W; 지정된 구역별 전력 부하: 13.9931; 지정된 구역별 조명 부하: 10.7639; 지정된 전력 부하: 0 W; 지정된 조명 부하: 0 W; 천장속 조명 방사: 20; 총 개인별 열 취득: 131.882 W
치수 - 계산 높이: 1000 mm; 둘레: 89909.9 mm; 면적: 96.6244 m2; 무한한 높이: 3080 mm; 체적: 297.603 m3

# IfcSpace: 복도 308:3694916, 308
In: 지상 10층
LongName: 복도; InteriorOrExteriorSpace: INTERNAL
Pset_SpaceCommon - Reference: 복도 308; FloorCovering: T30 화강석 물갈기; WallCovering: 수성페인트; CeilingCovering: T6무석면택스마감
BaseQuantities - NetFloorArea: 96.3696 m2; Height: 3580 mm; GrossFloorArea: 96.3696 m2; GrossVolume: 345.003 m3
ID 데이터 - 바닥 마감: T30 화강석 물갈기; 번호: 308; 베이스 마감: 목재 걸레받이; 벽 마감: 수성페인트; 이름: 복도; 천장 마감: T6무석면택스마감
공정 - 공정: 새 구성
구속조건 - 베이스 간격띄우기: 0 mm; 상한값: 지상 10층; 레벨: 지상 10층; 한계 간격띄우기: 3580 mm
기타 - 거실여부: no; 공정 ID: 0; 카테고리: 룸; 공간분류코드: 33105; 실ID: 1004
에너지 해석 - 구역별 실제 전력 부하: 0; 구역별 실제 조명 부하: 0; 기초 전력 부하: 공간 유형별; 기초 조명 부하: 공간 유형별; 사람 수: 0; 열 부하 값: 공간 유형별; 전력 부하 단위: 전력 밀도; 조명 부하 단위: 전력 밀도; 1인당 잠열 취득: 58.6142 W; 1인당 현열 취득: 73.2678 W; 개인별 면적: 28.5714 m2; 실제 전력 부하: 0 W; 실제 조명 부하: 0 W; 지정된 구역별 전력 부하: 13.9931; 지정된 구역별 조명 부하: 10.7639; 지정된 전력 부하: 0 W; 지정된 조명 부하: 0 W; 천장속 조명 방사: 20; 총 개인별 열 취득: 131.882 W
치수 - 계산 높이: 1000 mm; 둘레: 89502.3 mm; 면적: 96.3696 m2; 무한한 높이: 3580 mm; 체적: 337.294 m3

# IfcSpace: 복도 83:5256369, 83
In: 옥탑층
LongName: 복도; InteriorOrExteriorSpace: INTERNAL
Pset_SpaceCommon - Reference: 복도 83; FloorCovering: T30 화강석 물갈기; WallCovering: 수성페인트; CeilingCovering: T6무석면택스마감
BaseQuantities - NetFloorArea: 13.0078 m2; Height: 2680 mm; GrossPerimeter: 17007.8 mm; GrossFloorArea: 13.0078 m2; GrossVolume: 34.8608 m3
ID 데이터 - 바닥 마감: T30 화강석 물갈기; 번호: 83; 베이스 마감: 목재 걸레받이; 벽 마감: 수성페인트; 이름: 복도; 천장 마감: T6무석면택스마감
공정 - 공정: 새 구성
구속조건 - 베이스 간격띄우기: 0 mm; 상한값: 옥탑층; 레벨: 옥탑층; 한계 간격띄우기: 2680 mm
기타 - 거실여부: no; 공정 ID: 0; 카테고리: 룸; 공간분류코드: 33105; 실ID: RF09
에너지 해석 - 구역별 실제 전력 부하: 0; 구역별 실제 조명 부하: 0; 기초 전력 부하: 공간 유형별; 기초 조명 부하: 공간 유형별; 사람 수: 0; 열 부하 값: 공간 유형별; 전력 부하 단위: 전력 밀도; 조명 부하 단위: 전력 밀도; 1인당 잠열 취득: 58.6142 W; 1인당 현열 취득: 73.2678 W; 개인별 면적: 28.5714 m2; 실제 전력 부하: 0 W; 실제 조명 부하: 0 W; 지정된 구역별 전력 부하: 13.9931; 지정된 구역별 조명 부하: 10.7639; 지정된 전력 부하: 0 W; 지정된 조명 부하: 0 W; 천장속 조명 방사: 20; 총 개인별 열 취득: 131.882 W
치수 - 계산 높이: 0 mm; 둘레: 17007.8 mm; 면적: 13.0078 m2; 무한한 높이: 2680 mm; 체적: 34.8608 m3

# IfcSpace: 사무실 102:6544223, 102
In: 지상 9층
LongName: 사무실; InteriorOrExteriorSpace: INTERNAL
Pset_SpaceCommon - Reference: 사무실 102; FloorCovering: T32 테라조타일; WallCovering: 수성페인트; CeilingCovering: T6무석면택스마감
BaseQuantities - NetFloorArea: 107.415 m2; Height: 3080 mm; GrossPerimeter: 43160.3 mm; GrossFloorArea: 107.415 m2; GrossVolume: 330.837 m3
ID 데이터 - 바닥 마감: T32 테라조타일; 번호: 102; 베이스 마감: PVC 걸레받이; 벽 마감: 수성페인트; 이름: 사무실; 천장 마감: T6무석면택스마감
공정 - 공정: 새 구성
구속조건 - 베이스 간격띄우기: 0 mm; 상한값: 지상 9층; 레벨: 지상 9층; 한계 간격띄우기: 3080 mm
기타 - 공정 ID: 0; 카테고리: 룸; 거실여부: yes; 공간분류코드: 33606; 실ID: 919
에너지 해석 - 구역별 실제 전력 부하: 0; 구역별 실제 조명 부하: 0; 기초 전력 부하: 공간 유형별; 기초 조명 부하: 공간 유형별; 사람 수: 0; 열 부하 값: 공간 유형별; 전력 부하 단위: 전력 밀도; 조명 부하 단위: 전력 밀도; 1인당 잠열 취득: 58.6142 W; 1인당 현열 취득: 73.2678 W; 개인별 면적: 28.5714 m2; 실제 전력 부하: 0 W; 실제 조명 부하: 0 W; 지정된 구역별 전력 부하: 13.9931; 지정된 구역별 조명 부하: 10.7639; 지정된 전력 부하: 0 W; 지정된 조명 부하: 0 W; 천장속 조명 방사: 20; 총 개인별 열 취득: 131.882 W
치수 - 계산 높이: 1000 mm; 둘레: 42776.7 mm; 면적: 107.415 m2; 무한한 높이: 3080 mm; 체적: 330.837 m3

# IfcSpace: 사무실 148:3691201, 148
In: 지상 1층
LongName: 사무실; InteriorOrExteriorSpace: INTERNAL
Pset_SpaceCommon - Reference: 사무실 148; FloorCovering: T32 테라조타일; WallCovering: 수성페인트; CeilingCovering: T6무석면택스마감
BaseQuantities - NetFloorArea: 61.0697 m2; Height: 3580 mm; GrossPerimeter: 40763.4 mm; GrossFloorArea: 61.0697 m2; GrossVolume: 218.63 m3
ID 데이터 - 바닥 마감: T32 테라조타일; 번호: 148; 베이스 마감: PVC 걸레받이; 벽 마감: 수성페인트; 이름: 사무실; 천장 마감: T6무석면택스마감
공정 - 공정: 새 구성
구속조건 - 베이스 간격띄우기: 0 mm; 상한값: 지상 1층; 레벨: 지상 1층; 한계 간격띄우기: 3580 mm
기타 - 공정 ID: 0; 카테고리: 룸; 거실여부: yes; 공간분류코드: 33606; 방화구획: yes; 실ID: 101
에너지 해석 - 구역별 실제 전력 부하: 0; 구역별 실제 조명 부하: 0; 기초 전력 부하: 공간 유형별; 기초 조명 부하: 공간 유형별; 사람 수: 0; 열 부하 값: 공간 유형별; 전력 부하 단위: 전력 밀도; 조명 부하 단위: 전력 밀도; 1인당 잠열 취득: 58.6142 W; 1인당 현열 취득: 73.2678 W; 개인별 면적: 28.5714 m2; 실제 전력 부하: 0 W; 실제 조명 부하: 0 W; 지정된 구역별 전력 부하: 13.9931; 지정된 구역별 조명 부하: 10.7639; 지정된 전력 부하: 0 W; 지정된 조명 부하: 0 W; 천장속 조명 방사: 20; 총 개인별 열 취득: 131.882 W
치수 - 계산 높이: 1000 mm; 둘레: 40754.4 mm; 면적: 61.0697 m2; 무한한 높이: 3580 mm; 체적: 218.63 m3

# IfcSpace: 사무실 149:3691205, 149
In: 지상 1층
LongName: 사무실; InteriorOrExteriorSpace: INTERNAL
Pset_SpaceCommon - Reference: 사무실 149; FloorCovering: T32 테라조타일; WallCovering: 수성페인트; CeilingCovering: T6무석면택스마감
BaseQuantities - NetFloorArea: 49.6049 m2; Height: 3580 mm; GrossPerimeter: 34011.9 mm; GrossFloorArea: 49.6049 m2; GrossVolume: 177.585 m3
ID 데이터 - 바닥 마감: T32 테라조타일; 번호: 149; 베이스 마감: PVC 걸레받이; 벽 마감: 수성페인트; 이름: 사무실; 천장 마감: T6무석면택스마감
공정 - 공정: 새 구성
구속조건 - 베이스 간격띄우기: 0 mm; 상한값: 지상 1층; 레벨: 지상 1층; 한계 간격띄우기: 3580 mm
기타 - 공정 ID: 0; 카테고리: 룸; 거실여부: yes; 방화구획: yes; 공간분류코드: 33606; 실ID: 102
에너지 해석 - 구역별 실제 전력 부하: 0; 구역별 실제 조명 부하: 0; 기초 전력 부하: 공간 유형별; 기초 조명 부하: 공간 유형별; 사람 수: 0; 열 부하 값: 공간 유형별; 전력 부하 단위: 전력 밀도; 조명 부하 단위: 전력 밀도; 1인당 잠열 취득: 58.6142 W; 1인당 현열 취득: 73.2678 W; 개인별 면적: 28.5714 m2; 실제 전력 부하: 0 W; 실제 조명 부하: 0 W; 지정된 구역별 전력 부하: 13.9931; 지정된 구역별 조명 부하: 10.7639; 지정된 전력 부하: 0 W; 지정된 조명 부하: 0 W; 천장속 조명 방사: 20; 총 개인별 열 취득: 131.882 W
치수 - 계산 높이: 1000 mm; 둘레: 34011.9 mm; 면적: 49.6049 m2; 무한한 높이: 3580 mm; 체적: 177.585 m3

# IfcSpace: 사무실 150:3691208, 150
In: 지상 1층
LongName: 사무실; InteriorOrExteriorSpace: INTERNAL
Pset_SpaceCommon - Reference: 사무실 150; FloorCovering: T32 테라조타일; WallCovering: 수성페인트; CeilingCovering: T6무석면택스마감
BaseQuantities - NetFloorArea: 51.9084 m2; Height: 3580 mm; GrossPerimeter: 34538.3 mm; GrossFloorArea: 51.9084 m2; GrossVolume: 185.832 m3
ID 데이터 - 바닥 마감: T32 테라조타일; 번호: 150; 베이스 마감: PVC 걸레받이; 벽 마감: 수성페인트; 이름: 사무실; 천장 마감: T6무석면택스마감
공정 - 공정: 새 구성
구속조건 - 베이스 간격띄우기: 0 mm; 상한값: 지상 1층; 레벨: 지상 1층; 한계 간격띄우기: 3580 mm
기타 - 공정 ID: 0; 카테고리: 룸; 거실여부: yes; 방화구획: yes; 공간분류코드: 33606; 실ID: 103
에너지 해석 - 구역별 실제 전력 부하: 0; 구역별 실제 조명 부하: 0; 기초 전력 부하: 공간 유형별; 기초 조명 부하: 공간 유형별; 사람 수: 0; 열 부하 값: 공간 유형별; 전력 부하 단위: 전력 밀도; 조명 부하 단위: 전력 밀도; 1인당 잠열 취득: 58.6142 W; 1인당 현열 취득: 73.2678 W; 개인별 면적: 28.5714 m2; 실제 전력 부하: 0 W; 실제 조명 부하: 0 W; 지정된 구역별 전력 부하: 13.9931; 지정된 구역별 조명 부하: 10.7639; 지정된 전력 부하: 0 W; 지정된 조명 부하: 0 W; 천장속 조명 방사: 20; 총 개인별 열 취득: 131.882 W
치수 - 계산 높이: 1000 mm; 둘레: 34538.3 mm; 면적: 51.9084 m2; 무한한 높이: 3580 mm; 체적: 185.832 m3

# IfcSpace: 사무실 151:3691211, 151
In: 지상 1층
LongName: 사무실; InteriorOrExteriorSpace: INTERNAL
Pset_SpaceCommon - Reference: 사무실 151; FloorCovering: T32 테라조타일; WallCovering: 수성페인트; CeilingCovering: T6무석면택스마감
BaseQuantities - NetFloorArea: 51.7917 m2; Height: 3580 mm; GrossPerimeter: 34528.3 mm; GrossFloorArea: 51.7917 m2; GrossVolume: 185.414 m3
ID 데이터 - 바닥 마감: T32 테라조타일; 번호: 151; 베이스 마감: PVC 걸레받이; 벽 마감: 수성페인트; 이름: 사무실; 천장 마감: T6무석면택스마감
공정 - 공정: 새 구성
구속조건 - 베이스 간격띄우기: 0 mm; 상한값: 지상 1층; 레벨: 지상 1층; 한계 간격띄우기: 3580 mm
기타 - 공정 ID: 0; 카테고리: 룸; 거실여부: yes; 방화구획: yes; 공간분류코드: 33606; 실ID: 104
에너지 해석 - 구역별 실제 전력 부하: 0; 구역별 실제 조명 부하: 0; 기초 전력 부하: 공간 유형별; 기초 조명 부하: 공간 유형별; 사람 수: 0; 열 부하 값: 공간 유형별; 전력 부하 단위: 전력 밀도; 조명 부하 단위: 전력 밀도; 1인당 잠열 취득: 58.6142 W; 1인당 현열 취득: 73.2678 W; 개인별 면적: 28.5714 m2; 실제 전력 부하: 0 W; 실제 조명 부하: 0 W; 지정된 구역별 전력 부하: 13.9931; 지정된 구역별 조명 부하: 10.7639; 지정된 전력 부하: 0 W; 지정된 조명 부하: 0 W; 천장속 조명 방사: 20; 총 개인별 열 취득: 131.882 W
치수 - 계산 높이: 1000 mm; 둘레: 34528.3 mm; 면적: 51.7917 m2; 무한한 높이: 3580 mm; 체적: 185.414 m3

# IfcSpace: 사무실 153:3691217, 153
In: 지상 1층
LongName: 사무실; InteriorOrExteriorSpace: INTERNAL
Pset_SpaceCommon - Reference: 사무실 153; FloorCovering: T32 테라조타일; WallCovering: 수성페인트; CeilingCovering: T6무석면택스마감
BaseQuantities - NetFloorArea: 52.3333 m2; Height: 3580 mm; GrossPerimeter: 34767.1 mm; GrossFloorArea: 52.3333 m2; GrossVolume: 187.353 m3
ID 데이터 - 바닥 마감: T32 테라조타일; 번호: 153; 베이스 마감: PVC 걸레받이; 벽 마감: 수성페인트; 이름: 사무실; 천장 마감: T6무석면택스마감
공정 - 공정: 새 구성
구속조건 - 베이스 간격띄우기: 0 mm; 상한값: 지상 1층; 레벨: 지상 1층; 한계 간격띄우기: 3580 mm
기타 - 공정 ID: 0; 카테고리: 룸; 거실여부: yes; 방화구획: yes; 공간분류코드: 33606; 실ID: 105
에너지 해석 - 구역별 실제 전력 부하: 0; 구역별 실제 조명 부하: 0; 기초 전력 부하: 공간 유형별; 기초 조명 부하: 공간 유형별; 사람 수: 0; 열 부하 값: 공간 유형별; 전력 부하 단위: 전력 밀도; 조명 부하 단위: 전력 밀도; 1인당 잠열 취득: 58.6142 W; 1인당 현열 취득: 73.2678 W; 개인별 면적: 28.5714 m2; 실제 전력 부하: 0 W; 실제 조명 부하: 0 W; 지정된 구역별 전력 부하: 13.9931; 지정된 구역별 조명 부하: 10.7639; 지정된 전력 부하: 0 W; 지정된 조명 부하: 0 W; 천장속 조명 방사: 20; 총 개인별 열 취득: 131.882 W
치수 - 계산 높이: 1000 mm; 둘레: 34758.1 mm; 면적: 52.3333 m2; 무한한 높이: 3580 mm; 체적: 187.353 m3

# IfcSpace: 사무실 154:3691220, 154
In: 지상 1층
LongName: 사무실; InteriorOrExteriorSpace: INTERNAL
Pset_SpaceCommon - Reference: 사무실 154; FloorCovering: T32 테라조타일; WallCovering: 수성페인트; CeilingCovering: T6무석면택스마감
BaseQuantities - NetFloorArea: 52.8943 m2; Height: 3580 mm; GrossPerimeter: 34431.1 mm; GrossFloorArea: 52.8943 m2; GrossVolume: 189.362 m3
ID 데이터 - 바닥 마감: T32 테라조타일; 번호: 154; 베이스 마감: PVC 걸레받이; 벽 마감: 수성페인트; 이름: 사무실; 천장 마감: T6무석면택스마감
공정 - 공정: 새 구성
구속조건 - 베이스 간격띄우기: 0 mm; 상한값: 지상 1층; 레벨: 지상 1층; 한계 간격띄우기: 3580 mm
기타 - 공정 ID: 0; 카테고리: 룸; 거실여부: yes; 방화구획: yes; 공간분류코드: 33606; 실ID: 106
에너지 해석 - 구역별 실제 전력 부하: 0; 구역별 실제 조명 부하: 0; 기초 전력 부하: 공간 유형별; 기초 조명 부하: 공간 유형별; 사람 수: 0; 열 부하 값: 공간 유형별; 전력 부하 단위: 전력 밀도; 조명 부하 단위: 전력 밀도; 1인당 잠열 취득: 58.6142 W; 1인당 현열 취득: 73.2678 W; 개인별 면적: 28.5714 m2; 실제 전력 부하: 0 W; 실제 조명 부하: 0 W; 지정된 구역별 전력 부하: 13.9931; 지정된 구역별 조명 부하: 10.7639; 지정된 전력 부하: 0 W; 지정된 조명 부하: 0 W; 천장속 조명 방사: 20; 총 개인별 열 취득: 131.882 W
치수 - 계산 높이: 1000 mm; 둘레: 34431.1 mm; 면적: 52.8943 m2; 무한한 높이: 3580 mm; 체적: 189.362 m3

# IfcSpace: 사무실 155:3691223, 155
In: 지상 1층
LongName: 사무실; InteriorOrExteriorSpace: INTERNAL
Pset_SpaceCommon - Reference: 사무실 155; FloorCovering: T32 테라조타일; WallCovering: 수성페인트; CeilingCovering: T6무석면택스마감
BaseQuantities - NetFloorArea: 51.7753 m2; Height: 3580 mm; GrossPerimeter: 34413 mm; GrossFloorArea: 51.7753 m2; GrossVolume: 185.356 m3
ID 데이터 - 바닥 마감: T32 테라조타일; 번호: 155; 베이스 마감: PVC 걸레받이; 벽 마감: 수성페인트; 이름: 사무실; 천장 마감: T6무석면택스마감
공정 - 공정: 새 구성
구속조건 - 베이스 간격띄우기: 0 mm; 상한값: 지상 1층; 레벨: 지상 1층; 한계 간격띄우기: 3580 mm
기타 - 공정 ID: 0; 카테고리: 룸; 거실여부: yes; 방화구획: yes; 공간분류코드: 33606; 실ID: 107
에너지 해석 - 구역별 실제 전력 부하: 0; 구역별 실제 조명 부하: 0; 기초 전력 부하: 공간 유형별; 기초 조명 부하: 공간 유형별; 사람 수: 0; 열 부하 값: 공간 유형별; 전력 부하 단위: 전력 밀도; 조명 부하 단위: 전력 밀도; 1인당 잠열 취득: 58.6142 W; 1인당 현열 취득: 73.2678 W; 개인별 면적: 28.5714 m2; 실제 전력 부하: 0 W; 실제 조명 부하: 0 W; 지정된 구역별 전력 부하: 13.9931; 지정된 구역별 조명 부하: 10.7639; 지정된 전력 부하: 0 W; 지정된 조명 부하: 0 W; 천장속 조명 방사: 20; 총 개인별 열 취득: 131.882 W
치수 - 계산 높이: 1000 mm; 둘레: 34413 mm; 면적: 51.7753 m2; 무한한 높이: 3580 mm; 체적: 185.356 m3

# IfcSpace: 사무실 156:3691229, 156
In: 지상 1층
LongName: 사무실; InteriorOrExteriorSpace: INTERNAL
Pset_SpaceCommon - Reference: 사무실 156; FloorCovering: T32 테라조타일; WallCovering: 수성페인트; CeilingCovering: T6무석면택스마감
BaseQuantities - NetFloorArea: 67.3163 m2; Height: 3580 mm; GrossPerimeter: 35727 mm; GrossFloorArea: 67.3163 m2; GrossVolume: 240.993 m3
ID 데이터 - 바닥 마감: T32 테라조타일; 번호: 156; 베이스 마감: PVC 걸레받이; 벽 마감: 수성페인트; 이름: 사무실; 천장 마감: T6무석면택스마감
공정 - 공정: 새 구성
구속조건 - 베이스 간격띄우기: 0 mm; 상한값: 지상 1층; 레벨: 지상 1층; 한계 간격띄우기: 3580 mm
기타 - 공정 ID: 0; 카테고리: 룸; 거실여부: yes; 방화구획: yes; 공간분류코드: 33606; 실ID: 108
에너지 해석 - 구역별 실제 전력 부하: 0; 구역별 실제 조명 부하: 0; 기초 전력 부하: 공간 유형별; 기초 조명 부하: 공간 유형별; 사람 수: 0; 열 부하 값: 공간 유형별; 전력 부하 단위: 전력 밀도; 조명 부하 단위: 전력 밀도; 1인당 잠열 취득: 58.6142 W; 1인당 현열 취득: 73.2678 W; 개인별 면적: 28.5714 m2; 실제 전력 부하: 0 W; 실제 조명 부하: 0 W; 지정된 구역별 전력 부하: 13.9931; 지정된 구역별 조명 부하: 10.7639; 지정된 전력 부하: 0 W; 지정된 조명 부하: 0 W; 천장속 조명 방사: 20; 총 개인별 열 취득: 131.882 W
치수 - 계산 높이: 1000 mm; 둘레: 34925.9 mm; 면적: 67.3163 m2; 무한한 높이: 3580 mm; 체적: 240.993 m3

# IfcSpace: 사무실 157:3691232, 157
In: 지상 1층
LongName: 사무실; InteriorOrExteriorSpace: INTERNAL
Pset_SpaceCommon - Reference: 사무실 157; FloorCovering: T32 테라조타일; WallCovering: 수성페인트; CeilingCovering: T6무석면택스마감
BaseQuantities - NetFloorArea: 64.8698 m2; Height: 3580 mm; GrossPerimeter: 35203 mm; GrossFloorArea: 64.8698 m2; GrossVolume: 232.234 m3
ID 데이터 - 바닥 마감: T32 테라조타일; 번호: 157; 베이스 마감: PVC 걸레받이; 벽 마감: 수성페인트; 이름: 사무실; 천장 마감: T6무석면택스마감
공정 - 공정: 새 구성
구속조건 - 베이스 간격띄우기: 0 mm; 상한값: 지상 1층; 레벨: 지상 1층; 한계 간격띄우기: 3580 mm
기타 - 공정 ID: 0; 카테고리: 룸; 거실여부: yes; 방화구획: yes; 공간분류코드: 33606; 실ID: 109
에너지 해석 - 구역별 실제 전력 부하: 0; 구역별 실제 조명 부하: 0; 기초 전력 부하: 공간 유형별; 기초 조명 부하: 공간 유형별; 사람 수: 0; 열 부하 값: 공간 유형별; 전력 부하 단위: 전력 밀도; 조명 부하 단위: 전력 밀도; 1인당 잠열 취득: 58.6142 W; 1인당 현열 취득: 73.2678 W; 개인별 면적: 28.5714 m2; 실제 전력 부하: 0 W; 실제 조명 부하: 0 W; 지정된 구역별 전력 부하: 13.9931; 지정된 구역별 조명 부하: 10.7639; 지정된 전력 부하: 0 W; 지정된 조명 부하: 0 W; 천장속 조명 방사: 20; 총 개인별 열 취득: 131.882 W
치수 - 계산 높이: 1000 mm; 둘레: 34807 mm; 면적: 64.8698 m2; 무한한 높이: 3580 mm; 체적: 232.234 m3

# IfcSpace: 사무실 158:3691235, 158
In: 지상 1층
LongName: 사무실; InteriorOrExteriorSpace: INTERNAL
Pset_SpaceCommon - Reference: 사무실 158; FloorCovering: T32 테라조타일; WallCovering: 수성페인트; CeilingCovering: T6무석면택스마감
BaseQuantities - NetFloorArea: 39.291 m2; Height: 3580 mm; GrossPerimeter: 28066.9 mm; GrossFloorArea: 39.291 m2; GrossVolume: 140.662 m3
ID 데이터 - 바닥 마감: T32 테라조타일; 번호: 158; 베이스 마감: PVC 걸레받이; 벽 마감: 수성페인트; 이름: 사무실; 천장 마감: T6무석면택스마감
공정 - 공정: 새 구성
구속조건 - 베이스 간격띄우기: 0 mm; 상한값: 지상 1층; 레벨: 지상 1층; 한계 간격띄우기: 3580 mm
기타 - 공정 ID: 0; 카테고리: 룸; 거실여부: yes; 방화구획: yes; 공간분류코드: 33606; 실ID: 110
에너지 해석 - 구역별 실제 전력 부하: 0; 구역별 실제 조명 부하: 0; 기초 전력 부하: 공간 유형별; 기초 조명 부하: 공간 유형별; 사람 수: 0; 열 부하 값: 공간 유형별; 전력 부하 단위: 전력 밀도; 조명 부하 단위: 전력 밀도; 1인당 잠열 취득: 58.6142 W; 1인당 현열 취득: 73.2678 W; 개인별 면적: 28.5714 m2; 실제 전력 부하: 0 W; 실제 조명 부하: 0 W; 지정된 구역별 전력 부하: 13.9931; 지정된 구역별 조명 부하: 10.7639; 지정된 전력 부하: 0 W; 지정된 조명 부하: 0 W; 천장속 조명 방사: 20; 총 개인별 열 취득: 131.882 W
치수 - 계산 높이: 1000 mm; 둘레: 28066.9 mm; 면적: 39.291 m2; 무한한 높이: 3580 mm; 체적: 140.662 m3

# IfcSpace: 사무실 159:3691238, 159
In: 지상 1층
LongName: 사무실; InteriorOrExteriorSpace: INTERNAL
Pset_SpaceCommon - Reference: 사무실 159; FloorCovering: T32 테라조타일; WallCovering: 수성페인트; CeilingCovering: T6무석면택스마감
BaseQuantities - NetFloorArea: 40.2531 m2; Height: 3580 mm; GrossPerimeter: 28119 mm; GrossFloorArea: 40.2531 m2; GrossVolume: 144.106 m3
ID 데이터 - 바닥 마감: T32 테라조타일; 번호: 159; 베이스 마감: PVC 걸레받이; 벽 마감: 수성페인트; 이름: 사무실; 천장 마감: T6무석면택스마감
공정 - 공정: 새 구성
구속조건 - 베이스 간격띄우기: 0 mm; 상한값: 지상 1층; 레벨: 지상 1층; 한계 간격띄우기: 3580 mm
기타 - 공정 ID: 0; 카테고리: 룸; 거실여부: yes; 방화구획: yes; 공간분류코드: 33606; 실ID: 111
에너지 해석 - 구역별 실제 전력 부하: 0; 구역별 실제 조명 부하: 0; 기초 전력 부하: 공간 유형별; 기초 조명 부하: 공간 유형별; 사람 수: 0; 열 부하 값: 공간 유형별; 전력 부하 단위: 전력 밀도; 조명 부하 단위: 전력 밀도; 1인당 잠열 취득: 58.6142 W; 1인당 현열 취득: 73.2678 W; 개인별 면적: 28.5714 m2; 실제 전력 부하: 0 W; 실제 조명 부하: 0 W; 지정된 구역별 전력 부하: 13.9931; 지정된 구역별 조명 부하: 10.7639; 지정된 전력 부하: 0 W; 지정된 조명 부하: 0 W; 천장속 조명 방사: 20; 총 개인별 열 취득: 131.882 W
치수 - 계산 높이: 1000 mm; 둘레: 28119 mm; 면적: 40.2531 m2; 무한한 높이: 3580 mm; 체적: 144.106 m3

# IfcSpace: 사무실 160:3691241, 160
In: 지상 1층
LongName: 사무실; InteriorOrExteriorSpace: INTERNAL
Pset_SpaceCommon - Reference: 사무실 160; FloorCovering: T32 테라조타일; WallCovering: 수성페인트; CeilingCovering: T6무석면택스마감
BaseQuantities - NetFloorArea: 39.1802 m2; Height: 3580 mm; GrossPerimeter: 28042 mm; GrossFloorArea: 39.1802 m2; GrossVolume: 140.265 m3
ID 데이터 - 바닥 마감: T32 테라조타일; 번호: 160; 베이스 마감: PVC 걸레받이; 벽 마감: 수성페인트; 이름: 사무실; 천장 마감: T6무석면택스마감
공정 - 공정: 새 구성
구속조건 - 베이스 간격띄우기: 0 mm; 상한값: 지상 1층; 레벨: 지상 1층; 한계 간격띄우기: 3580 mm
기타 - 공정 ID: 0; 카테고리: 룸; 거실여부: yes; 방화구획: yes; 공간분류코드: 33606; 실ID: 112
에너지 해석 - 구역별 실제 전력 부하: 0; 구역별 실제 조명 부하: 0; 기초 전력 부하: 공간 유형별; 기초 조명 부하: 공간 유형별; 사람 수: 0; 열 부하 값: 공간 유형별; 전력 부하 단위: 전력 밀도; 조명 부하 단위: 전력 밀도; 1인당 잠열 취득: 58.6142 W; 1인당 현열 취득: 73.2678 W; 개인별 면적: 28.5714 m2; 실제 전력 부하: 0 W; 실제 조명 부하: 0 W; 지정된 구역별 전력 부하: 13.9931; 지정된 구역별 조명 부하: 10.7639; 지정된 전력 부하: 0 W; 지정된 조명 부하: 0 W; 천장속 조명 방사: 20; 총 개인별 열 취득: 131.882 W
치수 - 계산 높이: 1000 mm; 둘레: 28042 mm; 면적: 39.1802 m2; 무한한 높이: 3580 mm; 체적: 140.265 m3

# IfcSpace: 사무실 1:3691749, 1
In: 지상 3층
LongName: 사무실; InteriorOrExteriorSpace: INTERNAL
Pset_SpaceCommon - Reference: 사무실 1; FloorCovering: T32 테라조타일; WallCovering: 수성페인트; CeilingCovering: T6무석면택스마감
BaseQuantities - NetFloorArea: 77.0229 m2; Height: 2980 mm; GrossPerimeter: 42410.7 mm; GrossFloorArea: 77.0229 m2; GrossVolume: 229.528 m3
ID 데이터 - 바닥 마감: T32 테라조타일; 번호: 1; 베이스 마감: PVC 걸레받이; 벽 마감: 수성페인트; 이름: 사무실; 천장 마감: T6무석면택스마감
공정 - 공정: 새 구성
구속조건 - 베이스 간격띄우기: 0 mm; 레벨: 지상 3층; 상한값: 지상 3층; 한계 간격띄우기: 2980 mm
기타 - 공정 ID: 0; 카테고리: 룸; 거실여부: yes; 방화구획: yes; 공간분류코드: 33606; 실ID: 301
에너지 해석 - 구역별 실제 전력 부하: 0; 구역별 실제 조명 부하: 0; 기초 전력 부하: 공간 유형별; 기초 조명 부하: 공간 유형별; 사람 수: 0; 열 부하 값: 공간 유형별; 전력 부하 단위: 전력 밀도; 조명 부하 단위: 전력 밀도; 1인당 잠열 취득: 58.6142 W; 1인당 현열 취득: 73.2678 W; 개인별 면적: 28.5714 m2; 실제 전력 부하: 0 W; 실제 조명 부하: 0 W; 지정된 구역별 전력 부하: 13.9931; 지정된 구역별 조명 부하: 10.7639; 지정된 전력 부하: 0 W; 지정된 조명 부하: 0 W; 천장속 조명 방사: 20; 총 개인별 열 취득: 131.882 W
치수 - 계산 높이: 1000 mm; 둘레: 41937.2 mm; 면적: 77.0229 m2; 무한한 높이: 2980 mm; 체적: 229.528 m3

# IfcSpace: 사무실 205:3692295, 205
In: 지상 4층
LongName: 사무실; InteriorOrExteriorSpace: INTERNAL
Pset_SpaceCommon - Reference: 사무실 205; FloorCovering: T32 테라조타일; WallCovering: 수성페인트; CeilingCovering: T6무석면택스마감
BaseQuantities - NetFloorArea: 122.848 m2; Height: 2980 mm; GrossPerimeter: 48692 mm; GrossFloorArea: 122.848 m2; GrossVolume: 366.086 m3
ID 데이터 - 바닥 마감: T32 테라조타일; 번호: 205; 베이스 마감: PVC 걸레받이; 벽 마감: 수성페인트; 이름: 사무실; 천장 마감: T6무석면택스마감
공정 - 공정: 새 구성
구속조건 - 베이스 간격띄우기: 0 mm; 레벨: 지상 4층; 상한값: 지상 4층; 한계 간격띄우기: 2980 mm
기타 - 공정 ID: 0; 카테고리: 룸; 거실여부: yes; 방화구획: yes; 공간분류코드: 33606; 실ID: 401
에너지 해석 - 구역별 실제 전력 부하: 0; 구역별 실제 조명 부하: 0; 기초 전력 부하: 공간 유형별; 기초 조명 부하: 공간 유형별; 사람 수: 0; 열 부하 값: 공간 유형별; 전력 부하 단위: 전력 밀도; 조명 부하 단위: 전력 밀도; 1인당 잠열 취득: 58.6142 W; 1인당 현열 취득: 73.2678 W; 개인별 면적: 28.5714 m2; 실제 전력 부하: 0 W; 실제 조명 부하: 0 W; 지정된 구역별 전력 부하: 13.9931; 지정된 구역별 조명 부하: 10.7639; 지정된 전력 부하: 0 W; 지정된 조명 부하: 0 W; 천장속 조명 방사: 20; 총 개인별 열 취득: 131.882 W
치수 - 계산 높이: 1000 mm; 둘레: 48692 mm; 면적: 122.848 m2; 무한한 높이: 2980 mm; 체적: 366.086 m3

# IfcSpace: 사무실 206:3692299, 206
In: 지상 4층
LongName: 사무실; InteriorOrExteriorSpace: INTERNAL
Pset_SpaceCommon - Reference: 사무실 206; FloorCovering: T32 테라조타일; WallCovering: 수성페인트; CeilingCovering: T6무석면택스마감
BaseQuantities - NetFloorArea: 106.375 m2; Height: 2980 mm; GrossPerimeter: 43023.2 mm; GrossFloorArea: 106.375 m2; GrossVolume: 316.997 m3
ID 데이터 - 바닥 마감: T32 테라조타일; 번호: 206; 베이스 마감: PVC 걸레받이; 벽 마감: 수성페인트; 이름: 사무실; 천장 마감: T6무석면택스마감
공정 - 공정: 새 구성
구속조건 - 베이스 간격띄우기: 0 mm; 상한값: 지상 4층; 레벨: 지상 4층; 한계 간격띄우기: 2980 mm
기타 - 공정 ID: 0; 카테고리: 룸; 거실여부: yes; 방화구획: yes; 공간분류코드: 33606; 실ID: 402
에너지 해석 - 구역별 실제 전력 부하: 0; 구역별 실제 조명 부하: 0; 기초 전력 부하: 공간 유형별; 기초 조명 부하: 공간 유형별; 사람 수: 0; 열 부하 값: 공간 유형별; 전력 부하 단위: 전력 밀도; 조명 부하 단위: 전력 밀도; 1인당 잠열 취득: 58.6142 W; 1인당 현열 취득: 73.2678 W; 개인별 면적: 28.5714 m2; 실제 전력 부하: 0 W; 실제 조명 부하: 0 W; 지정된 구역별 전력 부하: 13.9931; 지정된 구역별 조명 부하: 10.7639; 지정된 전력 부하: 0 W; 지정된 조명 부하: 0 W; 천장속 조명 방사: 20; 총 개인별 열 취득: 131.882 W
치수 - 계산 높이: 1000 mm; 둘레: 43023.2 mm; 면적: 106.375 m2; 무한한 높이: 2980 mm; 체적: 316.997 m3

# IfcSpace: 사무실 208:3692309, 208
In: 지상 4층
LongName: 사무실; InteriorOrExteriorSpace: INTERNAL
Pset_SpaceCommon - Reference: 사무실 208; FloorCovering: T32 테라조타일; WallCovering: 수성페인트; CeilingCovering: T6무석면택스마감
BaseQuantities - NetFloorArea: 196.178 m2; Height: 2980 mm; GrossPerimeter: 59923 mm; GrossFloorArea: 196.178 m2; GrossVolume: 584.61 m3
ID 데이터 - 바닥 마감: T32 테라조타일; 번호: 208; 베이스 마감: PVC 걸레받이; 벽 마감: 수성페인트; 이름: 사무실; 천장 마감: T6무석면택스마감
공정 - 공정: 새 구성
구속조건 - 베이스 간격띄우기: 0 mm; 상한값: 지상 4층; 레벨: 지상 4층; 한계 간격띄우기: 2980 mm
기타 - 공정 ID: 0; 카테고리: 룸; 거실여부: yes; 방화구획: yes; 공간분류코드: 33606; 실ID: 403
에너지 해석 - 구역별 실제 전력 부하: 0; 구역별 실제 조명 부하: 0; 기초 전력 부하: 공간 유형별; 기초 조명 부하: 공간 유형별; 사람 수: 0; 열 부하 값: 공간 유형별; 전력 부하 단위: 전력 밀도; 조명 부하 단위: 전력 밀도; 1인당 잠열 취득: 58.6142 W; 1인당 현열 취득: 73.2678 W; 개인별 면적: 28.5714 m2; 실제 전력 부하: 0 W; 실제 조명 부하: 0 W; 지정된 구역별 전력 부하: 13.9931; 지정된 구역별 조명 부하: 10.7639; 지정된 전력 부하: 0 W; 지정된 조명 부하: 0 W; 천장속 조명 방사: 20; 총 개인별 열 취득: 131.882 W
치수 - 계산 높이: 1000 mm; 둘레: 59449.5 mm; 면적: 196.178 m2; 무한한 높이: 2980 mm; 체적: 584.61 m3

# IfcSpace: 사무실 209:3692312, 209
In: 지상 4층
LongName: 사무실; InteriorOrExteriorSpace: INTERNAL
Pset_SpaceCommon - Reference: 사무실 209; FloorCovering: T32 테라조타일; WallCovering: 수성페인트; CeilingCovering: T6무석면택스마감
BaseQuantities - NetFloorArea: 130.247 m2; Height: 2980 mm; GrossPerimeter: 45987 mm; GrossFloorArea: 130.247 m2; GrossVolume: 388.136 m3
ID 데이터 - 바닥 마감: T32 테라조타일; 번호: 209; 베이스 마감: PVC 걸레받이; 벽 마감: 수성페인트; 이름: 사무실; 천장 마감: T6무석면택스마감
공정 - 공정: 새 구성
구속조건 - 베이스 간격띄우기: 0 mm; 상한값: 지상 4층; 레벨: 지상 4층; 한계 간격띄우기: 2980 mm
기타 - 공정 ID: 0; 카테고리: 룸; 거실여부: yes; 방화구획: yes; 공간분류코드: 33606; 실ID: 404
에너지 해석 - 구역별 실제 전력 부하: 0; 구역별 실제 조명 부하: 0; 기초 전력 부하: 공간 유형별; 기초 조명 부하: 공간 유형별; 사람 수: 0; 열 부하 값: 공간 유형별; 전력 부하 단위: 전력 밀도; 조명 부하 단위: 전력 밀도; 1인당 잠열 취득: 58.6142 W; 1인당 현열 취득: 73.2678 W; 개인별 면적: 28.5714 m2; 실제 전력 부하: 0 W; 실제 조명 부하: 0 W; 지정된 구역별 전력 부하: 13.9931; 지정된 구역별 조명 부하: 10.7639; 지정된 전력 부하: 0 W; 지정된 조명 부하: 0 W; 천장속 조명 방사: 20; 총 개인별 열 취득: 131.882 W
치수 - 계산 높이: 1000 mm; 둘레: 45987 mm; 면적: 130.247 m2; 무한한 높이: 2980 mm; 체적: 388.136 m3

# IfcSpace: 사무실 210:3692315, 210
In: 지상 4층
LongName: 사무실; InteriorOrExteriorSpace: INTERNAL
Pset_SpaceCommon - Reference: 사무실 210; FloorCovering: T32 테라조타일; WallCovering: 수성페인트; CeilingCovering: T6무석면택스마감
BaseQuantities - NetFloorArea: 149.756 m2; Height: 2980 mm; GrossPerimeter: 53057.9 mm; GrossFloorArea: 149.756 m2; GrossVolume: 446.273 m3
ID 데이터 - 바닥 마감: T32 테라조타일; 번호: 210; 베이스 마감: PVC 걸레받이; 벽 마감: 수성페인트; 이름: 사무실; 천장 마감: T6무석면택스마감
공정 - 공정: 새 구성
구속조건 - 베이스 간격띄우기: 0 mm; 상한값: 지상 4층; 레벨: 지상 4층; 한계 간격띄우기: 2980 mm
기타 - 공정 ID: 0; 카테고리: 룸; 거실여부: yes; 방화구획: yes; 공간분류코드: 33606; 실ID: 405
에너지 해석 - 구역별 실제 전력 부하: 0; 구역별 실제 조명 부하: 0; 기초 전력 부하: 공간 유형별; 기초 조명 부하: 공간 유형별; 사람 수: 0; 열 부하 값: 공간 유형별; 전력 부하 단위: 전력 밀도; 조명 부하 단위: 전력 밀도; 1인당 잠열 취득: 58.6142 W; 1인당 현열 취득: 73.2678 W; 개인별 면적: 28.5714 m2; 실제 전력 부하: 0 W; 실제 조명 부하: 0 W; 지정된 구역별 전력 부하: 13.9931; 지정된 구역별 조명 부하: 10.7639; 지정된 전력 부하: 0 W; 지정된 조명 부하: 0 W; 천장속 조명 방사: 20; 총 개인별 열 취득: 131.882 W
치수 - 계산 높이: 1000 mm; 둘레: 52347.6 mm; 면적: 149.756 m2; 무한한 높이: 2980 mm; 체적: 446.273 m3

# IfcSpace: 사무실 211:3692318, 211
In: 지상 4층
LongName: 사무실; InteriorOrExteriorSpace: INTERNAL
Pset_SpaceCommon - Reference: 사무실 211; FloorCovering: T32 테라조타일; WallCovering: 수성페인트; CeilingCovering: T6무석면택스마감
BaseQuantities - NetFloorArea: 138.748 m2; Height: 2980 mm; GrossPerimeter: 50748 mm; GrossFloorArea: 138.748 m2; GrossVolume: 413.468 m3
ID 데이터 - 바닥 마감: T32 테라조타일; 번호: 211; 베이스 마감: PVC 걸레받이; 벽 마감: 수성페인트; 이름: 사무실; 천장 마감: T6무석면택스마감
공정 - 공정: 새 구성
구속조건 - 베이스 간격띄우기: 0 mm; 상한값: 지상 4층; 레벨: 지상 4층; 한계 간격띄우기: 2980 mm
기타 - 공정 ID: 0; 카테고리: 룸; 거실여부: yes; 방화구획: yes; 공간분류코드: 33606; 실ID: 406
에너지 해석 - 구역별 실제 전력 부하: 0; 구역별 실제 조명 부하: 0; 기초 전력 부하: 공간 유형별; 기초 조명 부하: 공간 유형별; 사람 수: 0; 열 부하 값: 공간 유형별; 전력 부하 단위: 전력 밀도; 조명 부하 단위: 전력 밀도; 1인당 잠열 취득: 58.6142 W; 1인당 현열 취득: 73.2678 W; 개인별 면적: 28.5714 m2; 실제 전력 부하: 0 W; 실제 조명 부하: 0 W; 지정된 구역별 전력 부하: 13.9931; 지정된 구역별 조명 부하: 10.7639; 지정된 전력 부하: 0 W; 지정된 조명 부하: 0 W; 천장속 조명 방사: 20; 총 개인별 열 취득: 131.882 W
치수 - 계산 높이: 1000 mm; 둘레: 49800.9 mm; 면적: 138.748 m2; 무한한 높이: 2980 mm; 체적: 413.468 m3

# IfcSpace: 사무실 227:3692931, 227
In: 지상 5층
LongName: 사무실; InteriorOrExteriorSpace: INTERNAL
Pset_SpaceCommon - Reference: 사무실 227; FloorCovering: T32 테라조타일; WallCovering: 수성페인트; CeilingCovering: T6무석면택스마감
BaseQuantities - NetFloorArea: 123.34 m2; Height: 2980 mm; GrossPerimeter: 48919.1 mm; GrossFloorArea: 123.34 m2; GrossVolume: 367.553 m3
ID 데이터 - 바닥 마감: T32 테라조타일; 번호: 227; 베이스 마감: PVC 걸레받이; 벽 마감: 수성페인트; 이름: 사무실; 천장 마감: T6무석면택스마감
공정 - 공정: 새 구성
구속조건 - 베이스 간격띄우기: 0 mm; 상한값: 지상 5층; 레벨: 지상 5층; 한계 간격띄우기: 2980 mm
기타 - 공정 ID: 0; 카테고리: 룸; 거실여부: yes; 방화구획: yes; 공간분류코드: 33606; 실ID: 504
에너지 해석 - 구역별 실제 전력 부하: 0; 구역별 실제 조명 부하: 0; 기초 전력 부하: 공간 유형별; 기초 조명 부하: 공간 유형별; 사람 수: 0; 열 부하 값: 공간 유형별; 전력 부하 단위: 전력 밀도; 조명 부하 단위: 전력 밀도; 1인당 잠열 취득: 58.6142 W; 1인당 현열 취득: 73.2678 W; 개인별 면적: 28.5714 m2; 실제 전력 부하: 0 W; 실제 조명 부하: 0 W; 지정된 구역별 전력 부하: 13.9931; 지정된 구역별 조명 부하: 10.7639; 지정된 전력 부하: 0 W; 지정된 조명 부하: 0 W; 천장속 조명 방사: 20; 총 개인별 열 취득: 131.882 W
치수 - 계산 높이: 1000 mm; 둘레: 48445.6 mm; 면적: 123.34 m2; 무한한 높이: 2980 mm; 체적: 367.553 m3

# IfcSpace: 사무실 228:3692934, 228
In: 지상 5층
LongName: 사무실; InteriorOrExteriorSpace: INTERNAL
Pset_SpaceCommon - Reference: 사무실 228; FloorCovering: T32 테라조타일; WallCovering: 수성페인트; CeilingCovering: T6무석면택스마감
BaseQuantities - NetFloorArea: 106.825 m2; Height: 2980 mm; GrossPerimeter: 43160.3 mm; GrossFloorArea: 106.825 m2; GrossVolume: 318.34 m3
ID 데이터 - 바닥 마감: T32 테라조타일; 번호: 228; 베이스 마감: PVC 걸레받이; 벽 마감: 수성페인트; 이름: 사무실; 천장 마감: T6무석면택스마감
공정 - 공정: 새 구성
구속조건 - 베이스 간격띄우기: 0 mm; 상한값: 지상 5층; 레벨: 지상 5층; 한계 간격띄우기: 2980 mm
기타 - 공정 ID: 0; 카테고리: 룸; 거실여부: yes; 방화구획: yes; 공간분류코드: 33606; 실ID: 505
에너지 해석 - 구역별 실제 전력 부하: 0; 구역별 실제 조명 부하: 0; 기초 전력 부하: 공간 유형별; 기초 조명 부하: 공간 유형별; 사람 수: 0; 열 부하 값: 공간 유형별; 전력 부하 단위: 전력 밀도; 조명 부하 단위: 전력 밀도; 1인당 잠열 취득: 58.6142 W; 1인당 현열 취득: 73.2678 W; 개인별 면적: 28.5714 m2; 실제 전력 부하: 0 W; 실제 조명 부하: 0 W; 지정된 구역별 전력 부하: 13.9931; 지정된 구역별 조명 부하: 10.7639; 지정된 전력 부하: 0 W; 지정된 조명 부하: 0 W; 천장속 조명 방사: 20; 총 개인별 열 취득: 131.882 W
치수 - 계산 높이: 1000 mm; 둘레: 42721.2 mm; 면적: 106.825 m2; 무한한 높이: 2980 mm; 체적: 318.34 m3

# IfcSpace: 사무실 229:3692937, 229
In: 지상 5층
LongName: 사무실; InteriorOrExteriorSpace: INTERNAL
Pset_SpaceCommon - Reference: 사무실 229; FloorCovering: T32 테라조타일; WallCovering: 수성페인트; CeilingCovering: T6무석면택스마감
BaseQuantities - NetFloorArea: 86.1678 m2; Height: 2980 mm; GrossPerimeter: 39724.1 mm; GrossFloorArea: 86.1678 m2; GrossVolume: 256.78 m3
ID 데이터 - 바닥 마감: T32 테라조타일; 번호: 229; 베이스 마감: PVC 걸레받이; 벽 마감: 수성페인트; 이름: 사무실; 천장 마감: T6무석면택스마감
공정 - 공정: 새 구성
구속조건 - 베이스 간격띄우기: 0 mm; 상한값: 지상 5층; 레벨: 지상 5층; 한계 간격띄우기: 2980 mm
기타 - 공정 ID: 0; 카테고리: 룸; 거실여부: yes; 방화구획: yes; 공간분류코드: 33606; 실ID: 506
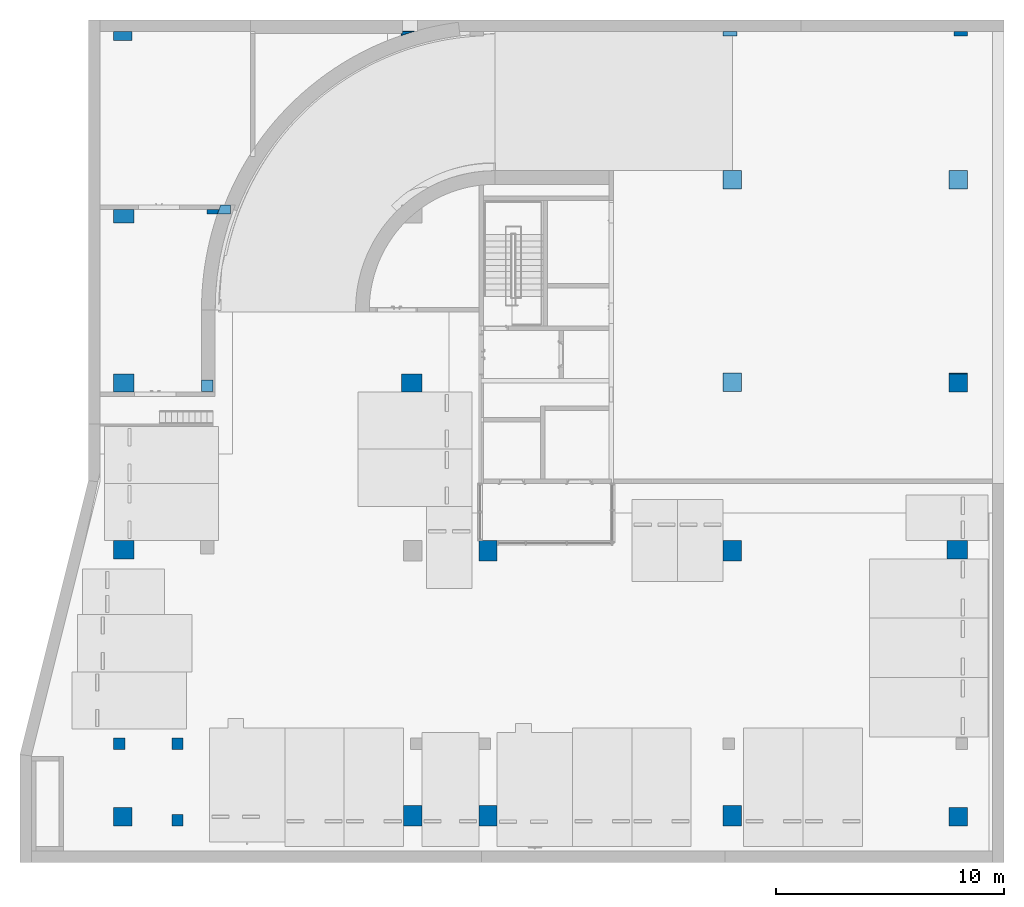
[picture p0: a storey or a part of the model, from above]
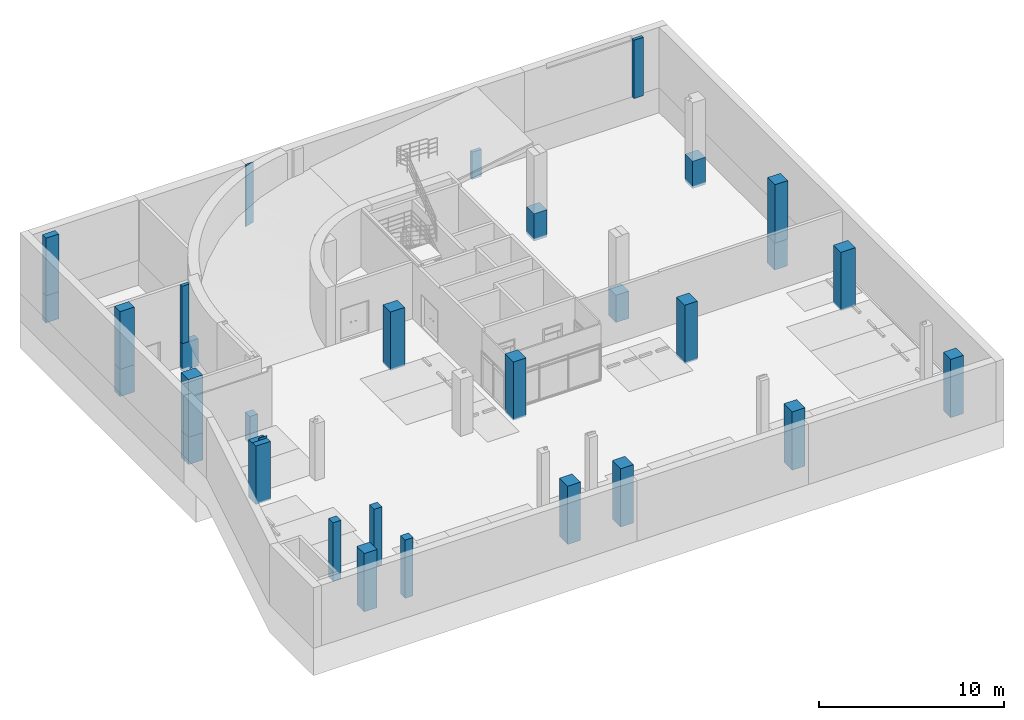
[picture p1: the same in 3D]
Properties of the parts of a building model (IFC2X3), part 3 of 39

# IfcSpace: 사무실 229:3692937, 229
에너지 해석 - 구역별 실제 전력 부하: 0; 구역별 실제 조명 부하: 0; 기초 전력 부하: 공간 유형별; 기초 조명 부하: 공간 유형별; 사람 수: 0; 열 부하 값: 공간 유형별; 전력 부하 단위: 전력 밀도; 조명 부하 단위: 전력 밀도; 1인당 잠열 취득: 58.6142 W; 1인당 현열 취득: 73.2678 W; 개인별 면적: 28.5714 m2; 실제 전력 부하: 0 W; 실제 조명 부하: 0 W; 지정된 구역별 전력 부하: 13.9931; 지정된 구역별 조명 부하: 10.7639; 지정된 전력 부하: 0 W; 지정된 조명 부하: 0 W; 천장속 조명 방사: 20; 총 개인별 열 취득: 131.882 W
치수 - 계산 높이: 1000 mm; 둘레: 39250.6 mm; 면적: 86.1678 m2; 무한한 높이: 2980 mm; 체적: 256.78 m3

# IfcSpace: 사무실 230:3692940, 230
In: 지상 5층
LongName: 사무실; InteriorOrExteriorSpace: INTERNAL
Pset_SpaceCommon - Reference: 사무실 230; FloorCovering: T32 테라조타일; WallCovering: 수성페인트; CeilingCovering: T6무석면택스마감
BaseQuantities - NetFloorArea: 196.184 m2; Height: 2980 mm; GrossPerimeter: 59924.2 mm; GrossFloorArea: 196.184 m2; GrossVolume: 584.629 m3
ID 데이터 - 바닥 마감: T32 테라조타일; 번호: 230; 베이스 마감: PVC 걸레받이; 벽 마감: 수성페인트; 이름: 사무실; 천장 마감: T6무석면택스마감
공정 - 공정: 새 구성
구속조건 - 베이스 간격띄우기: 0 mm; 상한값: 지상 5층; 레벨: 지상 5층; 한계 간격띄우기: 2980 mm
기타 - 공정 ID: 0; 카테고리: 룸; 거실여부: yes; 방화구획: yes; 공간분류코드: 33606; 실ID: 507
에너지 해석 - 구역별 실제 전력 부하: 0; 구역별 실제 조명 부하: 0; 기초 전력 부하: 공간 유형별; 기초 조명 부하: 공간 유형별; 사람 수: 0; 열 부하 값: 공간 유형별; 전력 부하 단위: 전력 밀도; 조명 부하 단위: 전력 밀도; 1인당 잠열 취득: 58.6142 W; 1인당 현열 취득: 73.2678 W; 개인별 면적: 28.5714 m2; 실제 전력 부하: 0 W; 실제 조명 부하: 0 W; 지정된 구역별 전력 부하: 13.9931; 지정된 구역별 조명 부하: 10.7639; 지정된 전력 부하: 0 W; 지정된 조명 부하: 0 W; 천장속 조명 방사: 20; 총 개인별 열 취득: 131.882 W
치수 - 계산 높이: 1000 mm; 둘레: 59450.6 mm; 면적: 196.184 m2; 무한한 높이: 2980 mm; 체적: 584.629 m3

# IfcSpace: 사무실 231:3692943, 231
In: 지상 5층
LongName: 사무실; InteriorOrExteriorSpace: INTERNAL
Pset_SpaceCommon - Reference: 사무실 231; FloorCovering: T32 테라조타일; WallCovering: 수성페인트; CeilingCovering: T6무석면택스마감
BaseQuantities - NetFloorArea: 130.247 m2; Height: 2980 mm; GrossPerimeter: 45987 mm; GrossFloorArea: 130.247 m2; GrossVolume: 388.136 m3
ID 데이터 - 바닥 마감: T32 테라조타일; 번호: 231; 베이스 마감: PVC 걸레받이; 벽 마감: 수성페인트; 이름: 사무실; 천장 마감: T6무석면택스마감
공정 - 공정: 새 구성
구속조건 - 베이스 간격띄우기: 0 mm; 상한값: 지상 5층; 레벨: 지상 5층; 한계 간격띄우기: 2980 mm
기타 - 공정 ID: 0; 카테고리: 룸; 거실여부: yes; 방화구획: yes; 공간분류코드: 33606; 실ID: 508
에너지 해석 - 구역별 실제 전력 부하: 0; 구역별 실제 조명 부하: 0; 기초 전력 부하: 공간 유형별; 기초 조명 부하: 공간 유형별; 사람 수: 0; 열 부하 값: 공간 유형별; 전력 부하 단위: 전력 밀도; 조명 부하 단위: 전력 밀도; 1인당 잠열 취득: 58.6142 W; 1인당 현열 취득: 73.2678 W; 개인별 면적: 28.5714 m2; 실제 전력 부하: 0 W; 실제 조명 부하: 0 W; 지정된 구역별 전력 부하: 13.9931; 지정된 구역별 조명 부하: 10.7639; 지정된 전력 부하: 0 W; 지정된 조명 부하: 0 W; 천장속 조명 방사: 20; 총 개인별 열 취득: 131.882 W
치수 - 계산 높이: 1000 mm; 둘레: 45987 mm; 면적: 130.247 m2; 무한한 높이: 2980 mm; 체적: 388.136 m3

# IfcSpace: 사무실 232:3692946, 232
In: 지상 5층
LongName: 사무실; InteriorOrExteriorSpace: INTERNAL
Pset_SpaceCommon - Reference: 사무실 232; FloorCovering: T32 테라조타일; WallCovering: 수성페인트; CeilingCovering: T6무석면택스마감
BaseQuantities - NetFloorArea: 149.819 m2; Height: 2980 mm; GrossPerimeter: 53079.1 mm; GrossFloorArea: 149.819 m2; GrossVolume: 446.461 m3
ID 데이터 - 바닥 마감: T32 테라조타일; 번호: 232; 베이스 마감: PVC 걸레받이; 벽 마감: 수성페인트; 이름: 사무실; 천장 마감: T6무석면택스마감
공정 - 공정: 새 구성
구속조건 - 베이스 간격띄우기: 0 mm; 상한값: 지상 5층; 레벨: 지상 5층; 한계 간격띄우기: 2980 mm
기타 - 공정 ID: 0; 카테고리: 룸; 거실여부: yes; 방화구획: yes; 공간분류코드: 33606; 실ID: 509
에너지 해석 - 구역별 실제 전력 부하: 0; 구역별 실제 조명 부하: 0; 기초 전력 부하: 공간 유형별; 기초 조명 부하: 공간 유형별; 사람 수: 0; 열 부하 값: 공간 유형별; 전력 부하 단위: 전력 밀도; 조명 부하 단위: 전력 밀도; 1인당 잠열 취득: 58.6142 W; 1인당 현열 취득: 73.2678 W; 개인별 면적: 28.5714 m2; 실제 전력 부하: 0 W; 실제 조명 부하: 0 W; 지정된 구역별 전력 부하: 13.9931; 지정된 구역별 조명 부하: 10.7639; 지정된 전력 부하: 0 W; 지정된 조명 부하: 0 W; 천장속 조명 방사: 20; 총 개인별 열 취득: 131.882 W
치수 - 계산 높이: 1000 mm; 둘레: 52112.9 mm; 면적: 149.819 m2; 무한한 높이: 2980 mm; 체적: 446.461 m3

# IfcSpace: 사무실 233:3692949, 233
In: 지상 5층
LongName: 사무실; InteriorOrExteriorSpace: INTERNAL
Pset_SpaceCommon - Reference: 사무실 233; FloorCovering: T32 테라조타일; WallCovering: 수성페인트; CeilingCovering: T6무석면택스마감
BaseQuantities - NetFloorArea: 139.226 m2; Height: 2980 mm; GrossPerimeter: 50337.4 mm; GrossFloorArea: 139.226 m2; GrossVolume: 414.895 m3
ID 데이터 - 바닥 마감: T32 테라조타일; 번호: 233; 베이스 마감: PVC 걸레받이; 벽 마감: 수성페인트; 이름: 사무실; 천장 마감: T6무석면택스마감
공정 - 공정: 새 구성
구속조건 - 베이스 간격띄우기: 0 mm; 상한값: 지상 5층; 레벨: 지상 5층; 한계 간격띄우기: 2980 mm
기타 - 공정 ID: 0; 카테고리: 룸; 거실여부: yes; 방화구획: yes; 공간분류코드: 33606; 실ID: 510
에너지 해석 - 구역별 실제 전력 부하: 0; 구역별 실제 조명 부하: 0; 기초 전력 부하: 공간 유형별; 기초 조명 부하: 공간 유형별; 사람 수: 0; 열 부하 값: 공간 유형별; 전력 부하 단위: 전력 밀도; 조명 부하 단위: 전력 밀도; 1인당 잠열 취득: 58.6142 W; 1인당 현열 취득: 73.2678 W; 개인별 면적: 28.5714 m2; 실제 전력 부하: 0 W; 실제 조명 부하: 0 W; 지정된 구역별 전력 부하: 13.9931; 지정된 구역별 조명 부하: 10.7639; 지정된 전력 부하: 0 W; 지정된 조명 부하: 0 W; 천장속 조명 방사: 20; 총 개인별 열 취득: 131.882 W
치수 - 계산 높이: 1000 mm; 둘레: 49627 mm; 면적: 139.226 m2; 무한한 높이: 2980 mm; 체적: 414.895 m3

# IfcSpace: 사무실 242:3694127, 242
In: 지상 6층
LongName: 사무실; InteriorOrExteriorSpace: INTERNAL
Pset_SpaceCommon - Reference: 사무실 242; FloorCovering: T32 테라조타일; WallCovering: 수성페인트; CeilingCovering: T6무석면택스마감
BaseQuantities - NetFloorArea: 123.339 m2; Height: 2980 mm; GrossPerimeter: 48829.2 mm; GrossFloorArea: 123.339 m2; GrossVolume: 367.552 m3
ID 데이터 - 바닥 마감: T32 테라조타일; 번호: 242; 베이스 마감: PVC 걸레받이; 벽 마감: 수성페인트; 이름: 사무실; 천장 마감: T6무석면택스마감
공정 - 공정: 새 구성
구속조건 - 베이스 간격띄우기: 0 mm; 상한값: 지상 6층; 레벨: 지상 6층; 한계 간격띄우기: 2980 mm
기타 - 공정 ID: 0; 카테고리: 룸; 거실여부: yes; 방화구획: yes; 공간분류코드: 33606; 실ID: 604
에너지 해석 - 구역별 실제 전력 부하: 0; 구역별 실제 조명 부하: 0; 기초 전력 부하: 공간 유형별; 기초 조명 부하: 공간 유형별; 사람 수: 0; 열 부하 값: 공간 유형별; 전력 부하 단위: 전력 밀도; 조명 부하 단위: 전력 밀도; 1인당 잠열 취득: 58.6142 W; 1인당 현열 취득: 73.2678 W; 개인별 면적: 28.5714 m2; 실제 전력 부하: 0 W; 실제 조명 부하: 0 W; 지정된 구역별 전력 부하: 13.9931; 지정된 구역별 조명 부하: 10.7639; 지정된 전력 부하: 0 W; 지정된 조명 부하: 0 W; 천장속 조명 방사: 20; 총 개인별 열 취득: 131.882 W
치수 - 계산 높이: 1000 mm; 둘레: 48355.7 mm; 면적: 123.339 m2; 무한한 높이: 2980 mm; 체적: 367.552 m3

# IfcSpace: 사무실 243:3694129, 243
In: 지상 6층
LongName: 사무실; InteriorOrExteriorSpace: INTERNAL
Pset_SpaceCommon - Reference: 사무실 243; FloorCovering: T32 테라조타일; WallCovering: 수성페인트; CeilingCovering: T6무석면택스마감
BaseQuantities - NetFloorArea: 106.826 m2; Height: 2980 mm; GrossPerimeter: 43160.2 mm; GrossFloorArea: 106.826 m2; GrossVolume: 318.341 m3
ID 데이터 - 바닥 마감: T32 테라조타일; 번호: 243; 베이스 마감: PVC 걸레받이; 벽 마감: 수성페인트; 이름: 사무실; 천장 마감: T6무석면택스마감
공정 - 공정: 새 구성
구속조건 - 베이스 간격띄우기: 0 mm; 상한값: 지상 6층; 레벨: 지상 6층; 한계 간격띄우기: 2980 mm
기타 - 공정 ID: 0; 카테고리: 룸; 거실여부: yes; 방화구획: yes; 공간분류코드: 33606; 실ID: 605
에너지 해석 - 구역별 실제 전력 부하: 0; 구역별 실제 조명 부하: 0; 기초 전력 부하: 공간 유형별; 기초 조명 부하: 공간 유형별; 사람 수: 0; 열 부하 값: 공간 유형별; 전력 부하 단위: 전력 밀도; 조명 부하 단위: 전력 밀도; 1인당 잠열 취득: 58.6142 W; 1인당 현열 취득: 73.2678 W; 개인별 면적: 28.5714 m2; 실제 전력 부하: 0 W; 실제 조명 부하: 0 W; 지정된 구역별 전력 부하: 13.9931; 지정된 구역별 조명 부하: 10.7639; 지정된 전력 부하: 0 W; 지정된 조명 부하: 0 W; 천장속 조명 방사: 20; 총 개인별 열 취득: 131.882 W
치수 - 계산 높이: 1000 mm; 둘레: 42721.2 mm; 면적: 106.826 m2; 무한한 높이: 2980 mm; 체적: 318.341 m3

# IfcSpace: 사무실 244:3694131, 244
In: 지상 6층
LongName: 사무실; InteriorOrExteriorSpace: INTERNAL
Pset_SpaceCommon - Reference: 사무실 244; FloorCovering: T32 테라조타일; WallCovering: 수성페인트; CeilingCovering: T6무석면택스마감
BaseQuantities - NetFloorArea: 86.1677 m2; Height: 2980 mm; GrossPerimeter: 39724.2 mm; GrossFloorArea: 86.1677 m2; GrossVolume: 256.78 m3
ID 데이터 - 바닥 마감: T32 테라조타일; 번호: 244; 베이스 마감: PVC 걸레받이; 벽 마감: 수성페인트; 이름: 사무실; 천장 마감: T6무석면택스마감
공정 - 공정: 새 구성
구속조건 - 베이스 간격띄우기: 0 mm; 상한값: 지상 6층; 레벨: 지상 6층; 한계 간격띄우기: 2980 mm
기타 - 공정 ID: 0; 카테고리: 룸; 거실여부: yes; 방화구획: yes; 공간분류코드: 33606; 실ID: 606
에너지 해석 - 구역별 실제 전력 부하: 0; 구역별 실제 조명 부하: 0; 기초 전력 부하: 공간 유형별; 기초 조명 부하: 공간 유형별; 사람 수: 0; 열 부하 값: 공간 유형별; 전력 부하 단위: 전력 밀도; 조명 부하 단위: 전력 밀도; 1인당 잠열 취득: 58.6142 W; 1인당 현열 취득: 73.2678 W; 개인별 면적: 28.5714 m2; 실제 전력 부하: 0 W; 실제 조명 부하: 0 W; 지정된 구역별 전력 부하: 13.9931; 지정된 구역별 조명 부하: 10.7639; 지정된 전력 부하: 0 W; 지정된 조명 부하: 0 W; 천장속 조명 방사: 20; 총 개인별 열 취득: 131.882 W
치수 - 계산 높이: 1000 mm; 둘레: 39250.6 mm; 면적: 86.1677 m2; 무한한 높이: 2980 mm; 체적: 256.78 m3

# IfcSpace: 사무실 245:3694133, 245
In: 지상 6층
LongName: 사무실; InteriorOrExteriorSpace: INTERNAL
Pset_SpaceCommon - Reference: 사무실 245; FloorCovering: T32 테라조타일; WallCovering: 수성페인트; CeilingCovering: T6무석면택스마감
BaseQuantities - NetFloorArea: 196.184 m2; Height: 2980 mm; GrossPerimeter: 59924.3 mm; GrossFloorArea: 196.184 m2; GrossVolume: 584.63 m3
ID 데이터 - 바닥 마감: T32 테라조타일; 번호: 245; 베이스 마감: PVC 걸레받이; 벽 마감: 수성페인트; 이름: 사무실; 천장 마감: T6무석면택스마감
공정 - 공정: 새 구성
구속조건 - 베이스 간격띄우기: 0 mm; 상한값: 지상 6층; 레벨: 지상 6층; 한계 간격띄우기: 2980 mm
기타 - 공정 ID: 0; 카테고리: 룸; 거실여부: yes; 방화구획: yes; 공간분류코드: 33606; 실ID: 607
에너지 해석 - 구역별 실제 전력 부하: 0; 구역별 실제 조명 부하: 0; 기초 전력 부하: 공간 유형별; 기초 조명 부하: 공간 유형별; 사람 수: 0; 열 부하 값: 공간 유형별; 전력 부하 단위: 전력 밀도; 조명 부하 단위: 전력 밀도; 1인당 잠열 취득: 58.6142 W; 1인당 현열 취득: 73.2678 W; 개인별 면적: 28.5714 m2; 실제 전력 부하: 0 W; 실제 조명 부하: 0 W; 지정된 구역별 전력 부하: 13.9931; 지정된 구역별 조명 부하: 10.7639; 지정된 전력 부하: 0 W; 지정된 조명 부하: 0 W; 천장속 조명 방사: 20; 총 개인별 열 취득: 131.882 W
치수 - 계산 높이: 1000 mm; 둘레: 59450.7 mm; 면적: 196.184 m2; 무한한 높이: 2980 mm; 체적: 584.63 m3

# IfcSpace: 사무실 246:3694135, 246
In: 지상 6층
LongName: 사무실; InteriorOrExteriorSpace: INTERNAL
Pset_SpaceCommon - Reference: 사무실 246; FloorCovering: T32 테라조타일; WallCovering: 수성페인트; CeilingCovering: T6무석면택스마감
BaseQuantities - NetFloorArea: 130.247 m2; Height: 2980 mm; GrossPerimeter: 45987 mm; GrossFloorArea: 130.247 m2; GrossVolume: 388.135 m3
ID 데이터 - 바닥 마감: T32 테라조타일; 번호: 246; 베이스 마감: PVC 걸레받이; 벽 마감: 수성페인트; 이름: 사무실; 천장 마감: T6무석면택스마감
공정 - 공정: 새 구성
구속조건 - 베이스 간격띄우기: 0 mm; 상한값: 지상 6층; 레벨: 지상 6층; 한계 간격띄우기: 2980 mm
기타 - 공정 ID: 0; 카테고리: 룸; 거실여부: yes; 방화구획: yes; 공간분류코드: 33606; 실ID: 608
에너지 해석 - 구역별 실제 전력 부하: 0; 구역별 실제 조명 부하: 0; 기초 전력 부하: 공간 유형별; 기초 조명 부하: 공간 유형별; 사람 수: 0; 열 부하 값: 공간 유형별; 전력 부하 단위: 전력 밀도; 조명 부하 단위: 전력 밀도; 1인당 잠열 취득: 58.6142 W; 1인당 현열 취득: 73.2678 W; 개인별 면적: 28.5714 m2; 실제 전력 부하: 0 W; 실제 조명 부하: 0 W; 지정된 구역별 전력 부하: 13.9931; 지정된 구역별 조명 부하: 10.7639; 지정된 전력 부하: 0 W; 지정된 조명 부하: 0 W; 천장속 조명 방사: 20; 총 개인별 열 취득: 131.882 W
치수 - 계산 높이: 1000 mm; 둘레: 45987 mm; 면적: 130.247 m2; 무한한 높이: 2980 mm; 체적: 388.135 m3

# IfcSpace: 사무실 247:3694137, 247
In: 지상 6층
LongName: 사무실; InteriorOrExteriorSpace: INTERNAL
Pset_SpaceCommon - Reference: 사무실 247; FloorCovering: T32 테라조타일; WallCovering: 수성페인트; CeilingCovering: T6무석면택스마감
BaseQuantities - NetFloorArea: 149.784 m2; Height: 2980 mm; GrossPerimeter: 53057.9 mm; GrossFloorArea: 149.784 m2; GrossVolume: 446.357 m3
ID 데이터 - 바닥 마감: T32 테라조타일; 번호: 247; 베이스 마감: PVC 걸레받이; 벽 마감: 수성페인트; 이름: 사무실; 천장 마감: T6무석면택스마감
공정 - 공정: 새 구성
구속조건 - 베이스 간격띄우기: 0 mm; 상한값: 지상 6층; 레벨: 지상 6층; 한계 간격띄우기: 2980 mm
기타 - 공정 ID: 0; 카테고리: 룸; 거실여부: yes; 방화구획: yes; 공간분류코드: 33606; 실ID: 609
에너지 해석 - 구역별 실제 전력 부하: 0; 구역별 실제 조명 부하: 0; 기초 전력 부하: 공간 유형별; 기초 조명 부하: 공간 유형별; 사람 수: 0; 열 부하 값: 공간 유형별; 전력 부하 단위: 전력 밀도; 조명 부하 단위: 전력 밀도; 1인당 잠열 취득: 58.6142 W; 1인당 현열 취득: 73.2678 W; 개인별 면적: 28.5714 m2; 실제 전력 부하: 0 W; 실제 조명 부하: 0 W; 지정된 구역별 전력 부하: 13.9931; 지정된 구역별 조명 부하: 10.7639; 지정된 전력 부하: 0 W; 지정된 조명 부하: 0 W; 천장속 조명 방사: 20; 총 개인별 열 취득: 131.882 W
치수 - 계산 높이: 1000 mm; 둘레: 52138.3 mm; 면적: 149.784 m2; 무한한 높이: 2980 mm; 체적: 446.357 m3

# IfcSpace: 사무실 248:3694139, 248
In: 지상 6층
LongName: 사무실; InteriorOrExteriorSpace: INTERNAL
Pset_SpaceCommon - Reference: 사무실 248; FloorCovering: T32 테라조타일; WallCovering: 수성페인트; CeilingCovering: THK3 무석면택스마감
BaseQuantities - NetFloorArea: 139.276 m2; Height: 2980 mm; GrossPerimeter: 50348 mm; GrossFloorArea: 139.276 m2; GrossVolume: 415.041 m3
ID 데이터 - 바닥 마감: T32 테라조타일; 번호: 248; 베이스 마감: PVC 걸레받이; 벽 마감: 수성페인트; 이름: 사무실; 천장 마감: THK3 무석면택스마감
공정 - 공정: 새 구성
구속조건 - 베이스 간격띄우기: 0 mm; 상한값: 지상 6층; 레벨: 지상 6층; 한계 간격띄우기: 2980 mm
기타 - 공정 ID: 0; 카테고리: 룸; 거실여부: yes; 방화구획: yes; 공간분류코드: 33606; 실ID: 610
에너지 해석 - 구역별 실제 전력 부하: 0; 구역별 실제 조명 부하: 0; 기초 전력 부하: 공간 유형별; 기초 조명 부하: 공간 유형별; 사람 수: 0; 열 부하 값: 공간 유형별; 전력 부하 단위: 전력 밀도; 조명 부하 단위: 전력 밀도; 1인당 잠열 취득: 58.6142 W; 1인당 현열 취득: 73.2678 W; 개인별 면적: 28.5714 m2; 실제 전력 부하: 0 W; 실제 조명 부하: 0 W; 지정된 구역별 전력 부하: 13.9931; 지정된 구역별 조명 부하: 10.7639; 지정된 전력 부하: 0 W; 지정된 조명 부하: 0 W; 천장속 조명 방사: 20; 총 개인별 열 취득: 131.882 W
치수 - 계산 높이: 1000 mm; 둘레: 49637.7 mm; 면적: 139.276 m2; 무한한 높이: 2980 mm; 체적: 415.041 m3

# IfcSpace: 사무실 256:3694318, 256
In: 지상 7층
LongName: 사무실; InteriorOrExteriorSpace: INTERNAL
Pset_SpaceCommon - Reference: 사무실 256; FloorCovering: T32 테라조타일; WallCovering: 수성페인트; CeilingCovering: T6무석면택스마감
BaseQuantities - NetFloorArea: 123.339 m2; Height: 2980 mm; GrossPerimeter: 48829.2 mm; GrossFloorArea: 123.339 m2; GrossVolume: 367.551 m3
ID 데이터 - 바닥 마감: T32 테라조타일; 번호: 256; 베이스 마감: PVC 걸레받이; 벽 마감: 수성페인트; 이름: 사무실; 천장 마감: T6무석면택스마감
공정 - 공정: 새 구성
구속조건 - 베이스 간격띄우기: 0 mm; 레벨: 지상 7층; 상한값: 지상 7층; 한계 간격띄우기: 2980 mm
기타 - 공정 ID: 0; 카테고리: 룸; 거실여부: yes; 방화구획: yes; 공간분류코드: 33606; 실ID: 701
에너지 해석 - 구역별 실제 전력 부하: 0; 구역별 실제 조명 부하: 0; 기초 전력 부하: 공간 유형별; 기초 조명 부하: 공간 유형별; 사람 수: 0; 열 부하 값: 공간 유형별; 전력 부하 단위: 전력 밀도; 조명 부하 단위: 전력 밀도; 1인당 잠열 취득: 58.6142 W; 1인당 현열 취득: 73.2678 W; 개인별 면적: 28.5714 m2; 실제 전력 부하: 0 W; 실제 조명 부하: 0 W; 지정된 구역별 전력 부하: 13.9931; 지정된 구역별 조명 부하: 10.7639; 지정된 전력 부하: 0 W; 지정된 조명 부하: 0 W; 천장속 조명 방사: 20; 총 개인별 열 취득: 131.882 W
치수 - 계산 높이: 1000 mm; 둘레: 48355.7 mm; 면적: 123.339 m2; 무한한 높이: 2980 mm; 체적: 367.551 m3

# IfcSpace: 사무실 257:3694322, 257
In: 지상 7층
LongName: 사무실; InteriorOrExteriorSpace: INTERNAL
Pset_SpaceCommon - Reference: 사무실 257; FloorCovering: T32 테라조타일; WallCovering: 수성페인트; CeilingCovering: T6무석면택스마감
BaseQuantities - NetFloorArea: 106.826 m2; Height: 2980 mm; GrossPerimeter: 43160.2 mm; GrossFloorArea: 106.826 m2; GrossVolume: 318.341 m3
ID 데이터 - 바닥 마감: T32 테라조타일; 번호: 257; 베이스 마감: PVC 걸레받이; 벽 마감: 수성페인트; 이름: 사무실; 천장 마감: T6무석면택스마감
공정 - 공정: 새 구성
구속조건 - 베이스 간격띄우기: 0 mm; 상한값: 지상 7층; 레벨: 지상 7층; 한계 간격띄우기: 2980 mm
기타 - 공정 ID: 0; 카테고리: 룸; 거실여부: yes; 방화구획: yes; 공간분류코드: 33606; 실ID: 702
에너지 해석 - 구역별 실제 전력 부하: 0; 구역별 실제 조명 부하: 0; 기초 전력 부하: 공간 유형별; 기초 조명 부하: 공간 유형별; 사람 수: 0; 열 부하 값: 공간 유형별; 전력 부하 단위: 전력 밀도; 조명 부하 단위: 전력 밀도; 1인당 잠열 취득: 58.6142 W; 1인당 현열 취득: 73.2678 W; 개인별 면적: 28.5714 m2; 실제 전력 부하: 0 W; 실제 조명 부하: 0 W; 지정된 구역별 전력 부하: 13.9931; 지정된 구역별 조명 부하: 10.7639; 지정된 전력 부하: 0 W; 지정된 조명 부하: 0 W; 천장속 조명 방사: 20; 총 개인별 열 취득: 131.882 W
치수 - 계산 높이: 1000 mm; 둘레: 42776.7 mm; 면적: 106.826 m2; 무한한 높이: 2980 mm; 체적: 318.341 m3

# IfcSpace: 사무실 258:3694325, 258
In: 지상 7층
LongName: 사무실; InteriorOrExteriorSpace: INTERNAL
Pset_SpaceCommon - Reference: 사무실 258; FloorCovering: T32 테라조타일; WallCovering: 수성페인트; CeilingCovering: T6무석면택스마감
BaseQuantities - NetFloorArea: 86.1677 m2; Height: 2980 mm; GrossPerimeter: 39724.2 mm; GrossFloorArea: 86.1677 m2; GrossVolume: 256.78 m3
ID 데이터 - 바닥 마감: T32 테라조타일; 번호: 258; 베이스 마감: PVC 걸레받이; 벽 마감: 수성페인트; 이름: 사무실; 천장 마감: T6무석면택스마감
공정 - 공정: 새 구성
구속조건 - 베이스 간격띄우기: 0 mm; 상한값: 지상 7층; 레벨: 지상 7층; 한계 간격띄우기: 2980 mm
기타 - 공정 ID: 0; 카테고리: 룸; 거실여부: yes; 방화구획: yes; 공간분류코드: 33606; 실ID: 703
에너지 해석 - 구역별 실제 전력 부하: 0; 구역별 실제 조명 부하: 0; 기초 전력 부하: 공간 유형별; 기초 조명 부하: 공간 유형별; 사람 수: 0; 열 부하 값: 공간 유형별; 전력 부하 단위: 전력 밀도; 조명 부하 단위: 전력 밀도; 1인당 잠열 취득: 58.6142 W; 1인당 현열 취득: 73.2678 W; 개인별 면적: 28.5714 m2; 실제 전력 부하: 0 W; 실제 조명 부하: 0 W; 지정된 구역별 전력 부하: 13.9931; 지정된 구역별 조명 부하: 10.7639; 지정된 전력 부하: 0 W; 지정된 조명 부하: 0 W; 천장속 조명 방사: 20; 총 개인별 열 취득: 131.882 W
치수 - 계산 높이: 1000 mm; 둘레: 39250.6 mm; 면적: 86.1677 m2; 무한한 높이: 2980 mm; 체적: 256.78 m3

# IfcSpace: 사무실 259:3694328, 259
In: 지상 7층
LongName: 사무실; InteriorOrExteriorSpace: INTERNAL
Pset_SpaceCommon - Reference: 사무실 259; FloorCovering: T32 테라조타일; WallCovering: 수성페인트; CeilingCovering: T6무석면택스마감
BaseQuantities - NetFloorArea: 196.184 m2; Height: 2980 mm; GrossPerimeter: 59924.2 mm; GrossFloorArea: 196.184 m2; GrossVolume: 584.629 m3
ID 데이터 - 바닥 마감: T32 테라조타일; 번호: 259; 베이스 마감: PVC 걸레받이; 벽 마감: 수성페인트; 이름: 사무실; 천장 마감: T6무석면택스마감
공정 - 공정: 새 구성
구속조건 - 베이스 간격띄우기: 0 mm; 상한값: 지상 7층; 레벨: 지상 7층; 한계 간격띄우기: 2980 mm
기타 - 공정 ID: 0; 카테고리: 룸; 거실여부: yes; 방화구획: yes; 공간분류코드: 33606; 실ID: 704
에너지 해석 - 구역별 실제 전력 부하: 0; 구역별 실제 조명 부하: 0; 기초 전력 부하: 공간 유형별; 기초 조명 부하: 공간 유형별; 사람 수: 0; 열 부하 값: 공간 유형별; 전력 부하 단위: 전력 밀도; 조명 부하 단위: 전력 밀도; 1인당 잠열 취득: 58.6142 W; 1인당 현열 취득: 73.2678 W; 개인별 면적: 28.5714 m2; 실제 전력 부하: 0 W; 실제 조명 부하: 0 W; 지정된 구역별 전력 부하: 13.9931; 지정된 구역별 조명 부하: 10.7639; 지정된 전력 부하: 0 W; 지정된 조명 부하: 0 W; 천장속 조명 방사: 20; 총 개인별 열 취득: 131.882 W
치수 - 계산 높이: 1000 mm; 둘레: 59450.7 mm; 면적: 196.184 m2; 무한한 높이: 2980 mm; 체적: 584.629 m3

# IfcSpace: 사무실 260:3694331, 260
In: 지상 7층
LongName: 사무실; InteriorOrExteriorSpace: INTERNAL
Pset_SpaceCommon - Reference: 사무실 260; FloorCovering: T32 테라조타일; WallCovering: 수성페인트; CeilingCovering: T6무석면택스마감
BaseQuantities - NetFloorArea: 130.249 m2; Height: 2980 mm; GrossPerimeter: 45987.3 mm; GrossFloorArea: 130.249 m2; GrossVolume: 388.141 m3
ID 데이터 - 바닥 마감: T32 테라조타일; 번호: 260; 베이스 마감: PVC 걸레받이; 벽 마감: 수성페인트; 이름: 사무실; 천장 마감: T6무석면택스마감
공정 - 공정: 새 구성
구속조건 - 베이스 간격띄우기: 0 mm; 상한값: 지상 7층; 레벨: 지상 7층; 한계 간격띄우기: 2980 mm
기타 - 공정 ID: 0; 카테고리: 룸; 거실여부: yes; 방화구획: yes; 공간분류코드: 33606; 실ID: 705
에너지 해석 - 구역별 실제 전력 부하: 0; 구역별 실제 조명 부하: 0; 기초 전력 부하: 공간 유형별; 기초 조명 부하: 공간 유형별; 사람 수: 0; 열 부하 값: 공간 유형별; 전력 부하 단위: 전력 밀도; 조명 부하 단위: 전력 밀도; 1인당 잠열 취득: 58.6142 W; 1인당 현열 취득: 73.2678 W; 개인별 면적: 28.5714 m2; 실제 전력 부하: 0 W; 실제 조명 부하: 0 W; 지정된 구역별 전력 부하: 13.9931; 지정된 구역별 조명 부하: 10.7639; 지정된 전력 부하: 0 W; 지정된 조명 부하: 0 W; 천장속 조명 방사: 20; 총 개인별 열 취득: 131.882 W
치수 - 계산 높이: 1000 mm; 둘레: 45987.3 mm; 면적: 130.249 m2; 무한한 높이: 2980 mm; 체적: 388.141 m3

# IfcSpace: 사무실 261:3694334, 261
In: 지상 7층
LongName: 사무실; InteriorOrExteriorSpace: INTERNAL
Pset_SpaceCommon - Reference: 사무실 261; FloorCovering: T32 테라조타일; WallCovering: 수성페인트; CeilingCovering: T6무석면택스마감
BaseQuantities - NetFloorArea: 149.781 m2; Height: 2980 mm; GrossPerimeter: 53067.8 mm; GrossFloorArea: 149.781 m2; GrossVolume: 446.347 m3
ID 데이터 - 바닥 마감: T32 테라조타일; 번호: 261; 베이스 마감: PVC 걸레받이; 벽 마감: 수성페인트; 이름: 사무실; 천장 마감: T6무석면택스마감
공정 - 공정: 새 구성
구속조건 - 베이스 간격띄우기: 0 mm; 상한값: 지상 7층; 레벨: 지상 7층; 한계 간격띄우기: 2980 mm
기타 - 공정 ID: 0; 카테고리: 룸; 거실여부: yes; 방화구획: yes; 공간분류코드: 33606; 실ID: 706
에너지 해석 - 구역별 실제 전력 부하: 0; 구역별 실제 조명 부하: 0; 기초 전력 부하: 공간 유형별; 기초 조명 부하: 공간 유형별; 사람 수: 0; 열 부하 값: 공간 유형별; 전력 부하 단위: 전력 밀도; 조명 부하 단위: 전력 밀도; 1인당 잠열 취득: 58.6142 W; 1인당 현열 취득: 73.2678 W; 개인별 면적: 28.5714 m2; 실제 전력 부하: 0 W; 실제 조명 부하: 0 W; 지정된 구역별 전력 부하: 13.9931; 지정된 구역별 조명 부하: 10.7639; 지정된 전력 부하: 0 W; 지정된 조명 부하: 0 W; 천장속 조명 방사: 20; 총 개인별 열 취득: 131.882 W
치수 - 계산 높이: 1000 mm; 둘레: 52110.7 mm; 면적: 149.781 m2; 무한한 높이: 2980 mm; 체적: 446.347 m3

# IfcSpace: 사무실 262:3694337, 262
In: 지상 7층
LongName: 사무실; InteriorOrExteriorSpace: INTERNAL
Pset_SpaceCommon - Reference: 사무실 262; FloorCovering: T32 테라조타일; WallCovering: 수성페인트; CeilingCovering: T6무석면택스마감
BaseQuantities - NetFloorArea: 139.276 m2; Height: 2980 mm; GrossPerimeter: 50348 mm; GrossFloorArea: 139.276 m2; GrossVolume: 415.041 m3
ID 데이터 - 바닥 마감: T32 테라조타일; 번호: 262; 베이스 마감: PVC 걸레받이; 벽 마감: 수성페인트; 이름: 사무실; 천장 마감: T6무석면택스마감
공정 - 공정: 새 구성
구속조건 - 베이스 간격띄우기: 0 mm; 상한값: 지상 7층; 레벨: 지상 7층; 한계 간격띄우기: 2980 mm
기타 - 공정 ID: 0; 카테고리: 룸; 거실여부: yes; 방화구획: yes; 공간분류코드: 33606; 실ID: 707
에너지 해석 - 구역별 실제 전력 부하: 0; 구역별 실제 조명 부하: 0; 기초 전력 부하: 공간 유형별; 기초 조명 부하: 공간 유형별; 사람 수: 0; 열 부하 값: 공간 유형별; 전력 부하 단위: 전력 밀도; 조명 부하 단위: 전력 밀도; 1인당 잠열 취득: 58.6142 W; 1인당 현열 취득: 73.2678 W; 개인별 면적: 28.5714 m2; 실제 전력 부하: 0 W; 실제 조명 부하: 0 W; 지정된 구역별 전력 부하: 13.9931; 지정된 구역별 조명 부하: 10.7639; 지정된 전력 부하: 0 W; 지정된 조명 부하: 0 W; 천장속 조명 방사: 20; 총 개인별 열 취득: 131.882 W
치수 - 계산 높이: 1000 mm; 둘레: 49637.7 mm; 면적: 139.276 m2; 무한한 높이: 2980 mm; 체적: 415.041 m3

# IfcSpace: 사무실 271:3694535, 271
In: 지상 8층
LongName: 사무실; InteriorOrExteriorSpace: INTERNAL
Pset_SpaceCommon - Reference: 사무실 271; FloorCovering: T32 테라조타일; WallCovering: 수성페인트; CeilingCovering: T6무석면택스마감
BaseQuantities - NetFloorArea: 123.611 m2; Height: 2980 mm; GrossPerimeter: 48719.2 mm; GrossFloorArea: 123.611 m2; GrossVolume: 368.359 m3
ID 데이터 - 바닥 마감: T32 테라조타일; 번호: 271; 베이스 마감: PVC 걸레받이; 벽 마감: 수성페인트; 이름: 사무실; 천장 마감: T6무석면택스마감
공정 - 공정: 새 구성
구속조건 - 베이스 간격띄우기: 0 mm; 레벨: 지상 8층; 상한값: 지상 8층; 한계 간격띄우기: 2980 mm
기타 - 공정 ID: 0; 카테고리: 룸; 거실여부: yes; 공간분류코드: 33606; 실ID: 801
에너지 해석 - 구역별 실제 전력 부하: 0; 구역별 실제 조명 부하: 0; 기초 전력 부하: 공간 유형별; 기초 조명 부하: 공간 유형별; 사람 수: 0; 열 부하 값: 공간 유형별; 전력 부하 단위: 전력 밀도; 조명 부하 단위: 전력 밀도; 1인당 잠열 취득: 58.6142 W; 1인당 현열 취득: 73.2678 W; 개인별 면적: 28.5714 m2; 실제 전력 부하: 0 W; 실제 조명 부하: 0 W; 지정된 구역별 전력 부하: 13.9931; 지정된 구역별 조명 부하: 10.7639; 지정된 전력 부하: 0 W; 지정된 조명 부하: 0 W; 천장속 조명 방사: 20; 총 개인별 열 취득: 131.882 W
치수 - 계산 높이: 1000 mm; 둘레: 48482.5 mm; 면적: 123.611 m2; 무한한 높이: 2980 mm; 체적: 368.359 m3

# IfcSpace: 사무실 272:3694539, 272
In: 지상 8층
LongName: 사무실; InteriorOrExteriorSpace: INTERNAL
Pset_SpaceCommon - Reference: 사무실 272; FloorCovering: T32 테라조타일; WallCovering: 수성페인트; CeilingCovering: T6무석면택스마감
BaseQuantities - NetFloorArea: 107.407 m2; Height: 2980 mm; GrossPerimeter: 43160.2 mm; GrossFloorArea: 107.407 m2; GrossVolume: 320.073 m3
ID 데이터 - 바닥 마감: T32 테라조타일; 번호: 272; 베이스 마감: PVC 걸레받이; 벽 마감: 수성페인트; 이름: 사무실; 천장 마감: T6무석면택스마감
공정 - 공정: 새 구성
구속조건 - 베이스 간격띄우기: 0 mm; 상한값: 지상 8층; 레벨: 지상 8층; 한계 간격띄우기: 2980 mm
기타 - 공정 ID: 0; 카테고리: 룸; 거실여부: yes; 공간분류코드: 33606; 실ID: 802
에너지 해석 - 구역별 실제 전력 부하: 0; 구역별 실제 조명 부하: 0; 기초 전력 부하: 공간 유형별; 기초 조명 부하: 공간 유형별; 사람 수: 0; 열 부하 값: 공간 유형별; 전력 부하 단위: 전력 밀도; 조명 부하 단위: 전력 밀도; 1인당 잠열 취득: 58.6142 W; 1인당 현열 취득: 73.2678 W; 개인별 면적: 28.5714 m2; 실제 전력 부하: 0 W; 실제 조명 부하: 0 W; 지정된 구역별 전력 부하: 13.9931; 지정된 구역별 조명 부하: 10.7639; 지정된 전력 부하: 0 W; 지정된 조명 부하: 0 W; 천장속 조명 방사: 20; 총 개인별 열 취득: 131.882 W
치수 - 계산 높이: 1000 mm; 둘레: 42858.9 mm; 면적: 107.407 m2; 무한한 높이: 2980 mm; 체적: 320.073 m3

# IfcSpace: 사무실 273:3694542, 273
In: 지상 8층
LongName: 사무실; InteriorOrExteriorSpace: INTERNAL
Pset_SpaceCommon - Reference: 사무실 273; FloorCovering: T32 테라조타일; WallCovering: 수성페인트; CeilingCovering: T6무석면택스마감
BaseQuantities - NetFloorArea: 86.1681 m2; Height: 2980 mm; GrossPerimeter: 39724.2 mm; GrossFloorArea: 86.1681 m2; GrossVolume: 256.781 m3
ID 데이터 - 바닥 마감: T32 테라조타일; 번호: 273; 베이스 마감: PVC 걸레받이; 벽 마감: 수성페인트; 이름: 사무실; 천장 마감: T6무석면택스마감
공정 - 공정: 새 구성
구속조건 - 베이스 간격띄우기: 0 mm; 상한값: 지상 8층; 레벨: 지상 8층; 한계 간격띄우기: 2980 mm
기타 - 공정 ID: 0; 카테고리: 룸; 거실여부: yes; 공간분류코드: 33606; 실ID: 803
에너지 해석 - 구역별 실제 전력 부하: 0; 구역별 실제 조명 부하: 0; 기초 전력 부하: 공간 유형별; 기초 조명 부하: 공간 유형별; 사람 수: 0; 열 부하 값: 공간 유형별; 전력 부하 단위: 전력 밀도; 조명 부하 단위: 전력 밀도; 1인당 잠열 취득: 58.6142 W; 1인당 현열 취득: 73.2678 W; 개인별 면적: 28.5714 m2; 실제 전력 부하: 0 W; 실제 조명 부하: 0 W; 지정된 구역별 전력 부하: 13.9931; 지정된 구역별 조명 부하: 10.7639; 지정된 전력 부하: 0 W; 지정된 조명 부하: 0 W; 천장속 조명 방사: 20; 총 개인별 열 취득: 131.882 W
치수 - 계산 높이: 1000 mm; 둘레: 39250.7 mm; 면적: 86.1681 m2; 무한한 높이: 2980 mm; 체적: 256.781 m3

# IfcSpace: 사무실 277:3694554, 277
In: 지상 8층
LongName: 사무실; InteriorOrExteriorSpace: INTERNAL
Pset_SpaceCommon - Reference: 사무실 277; FloorCovering: T32 테라조타일; WallCovering: 수성페인트; CeilingCovering: T6무석면택스마감
BaseQuantities - NetFloorArea: 139.276 m2; Height: 2980 mm; GrossPerimeter: 50347.9 mm; GrossFloorArea: 139.276 m2; GrossVolume: 415.043 m3
ID 데이터 - 바닥 마감: T32 테라조타일; 번호: 277; 베이스 마감: PVC 걸레받이; 벽 마감: 수성페인트; 이름: 사무실; 천장 마감: T6무석면택스마감
공정 - 공정: 새 구성
구속조건 - 베이스 간격띄우기: 0 mm; 상한값: 지상 8층; 레벨: 지상 8층; 한계 간격띄우기: 2980 mm
기타 - 공정 ID: 0; 카테고리: 룸; 거실여부: yes; 공간분류코드: 33606; 실ID: 804
에너지 해석 - 구역별 실제 전력 부하: 0; 구역별 실제 조명 부하: 0; 기초 전력 부하: 공간 유형별; 기초 조명 부하: 공간 유형별; 사람 수: 0; 열 부하 값: 공간 유형별; 전력 부하 단위: 전력 밀도; 조명 부하 단위: 전력 밀도; 1인당 잠열 취득: 58.6142 W; 1인당 현열 취득: 73.2678 W; 개인별 면적: 28.5714 m2; 실제 전력 부하: 0 W; 실제 조명 부하: 0 W; 지정된 구역별 전력 부하: 13.9931; 지정된 구역별 조명 부하: 10.7639; 지정된 전력 부하: 0 W; 지정된 조명 부하: 0 W; 천장속 조명 방사: 20; 총 개인별 열 취득: 131.882 W
치수 - 계산 높이: 1000 mm; 둘레: 49637.6 mm; 면적: 139.276 m2; 무한한 높이: 2980 mm; 체적: 415.043 m3

# IfcSpace: 사무실 286:3694710, 286
In: 지상 9층
LongName: 사무실; InteriorOrExteriorSpace: INTERNAL
Pset_SpaceCommon - Reference: 사무실 286; FloorCovering: T32 테라조타일; WallCovering: 수성페인트; CeilingCovering: T6무석면택스마감
BaseQuantities - NetFloorArea: 77.2176 m2; Height: 3080 mm; GrossPerimeter: 42449.2 mm; GrossFloorArea: 77.2176 m2; GrossVolume: 237.83 m3
ID 데이터 - 바닥 마감: T32 테라조타일; 번호: 286; 베이스 마감: PVC 걸레받이; 벽 마감: 수성페인트; 이름: 사무실; 천장 마감: T6무석면택스마감
공정 - 공정: 새 구성
구속조건 - 베이스 간격띄우기: 0 mm; 레벨: 지상 9층; 상한값: 지상 9층; 한계 간격띄우기: 3080 mm
기타 - 공정 ID: 0; 카테고리: 룸; 거실여부: yes; 공간분류코드: 33606; 실ID: 901
에너지 해석 - 구역별 실제 전력 부하: 0; 구역별 실제 조명 부하: 0; 기초 전력 부하: 공간 유형별; 기초 조명 부하: 공간 유형별; 사람 수: 0; 열 부하 값: 공간 유형별; 전력 부하 단위: 전력 밀도; 조명 부하 단위: 전력 밀도; 1인당 잠열 취득: 58.6142 W; 1인당 현열 취득: 73.2678 W; 개인별 면적: 28.5714 m2; 실제 전력 부하: 0 W; 실제 조명 부하: 0 W; 지정된 구역별 전력 부하: 13.9931; 지정된 구역별 조명 부하: 10.7639; 지정된 전력 부하: 0 W; 지정된 조명 부하: 0 W; 천장속 조명 방사: 20; 총 개인별 열 취득: 131.882 W
치수 - 계산 높이: 1000 mm; 둘레: 41975.7 mm; 면적: 77.2176 m2; 무한한 높이: 3080 mm; 체적: 237.83 m3

# IfcSpace: 사무실 288:3694717, 288
In: 지상 9층
LongName: 사무실; InteriorOrExteriorSpace: INTERNAL
Pset_SpaceCommon - Reference: 사무실 288; FloorCovering: T32 테라조타일; WallCovering: 수성페인트; CeilingCovering: T6무석면택스마감
BaseQuantities - NetFloorArea: 86.1677 m2; Height: 3080 mm; GrossPerimeter: 39724.2 mm; GrossFloorArea: 86.1677 m2; GrossVolume: 265.396 m3
ID 데이터 - 바닥 마감: T32 테라조타일; 번호: 288; 베이스 마감: PVC 걸레받이; 벽 마감: 수성페인트; 이름: 사무실; 천장 마감: T6무석면택스마감
공정 - 공정: 새 구성
구속조건 - 베이스 간격띄우기: 0 mm; 상한값: 지상 9층; 레벨: 지상 9층; 한계 간격띄우기: 3080 mm
기타 - 공정 ID: 0; 카테고리: 룸; 거실여부: yes; 공간분류코드: 33606; 실ID: 902
에너지 해석 - 구역별 실제 전력 부하: 0; 구역별 실제 조명 부하: 0; 기초 전력 부하: 공간 유형별; 기초 조명 부하: 공간 유형별; 사람 수: 0; 열 부하 값: 공간 유형별; 전력 부하 단위: 전력 밀도; 조명 부하 단위: 전력 밀도; 1인당 잠열 취득: 58.6142 W; 1인당 현열 취득: 73.2678 W; 개인별 면적: 28.5714 m2; 실제 전력 부하: 0 W; 실제 조명 부하: 0 W; 지정된 구역별 전력 부하: 13.9931; 지정된 구역별 조명 부하: 10.7639; 지정된 전력 부하: 0 W; 지정된 조명 부하: 0 W; 천장속 조명 방사: 20; 총 개인별 열 취득: 131.882 W
치수 - 계산 높이: 1000 mm; 둘레: 39250.6 mm; 면적: 86.1677 m2; 무한한 높이: 3080 mm; 체적: 265.396 m3

# IfcSpace: 사무실 292:3694729, 292
In: 지상 9층
LongName: 사무실; InteriorOrExteriorSpace: INTERNAL
Pset_SpaceCommon - Reference: 사무실 292; FloorCovering: T32 테라조타일; WallCovering: 수성페인트; CeilingCovering: T6무석면택스마감
BaseQuantities - NetFloorArea: 139.284 m2; Height: 3080 mm; GrossPerimeter: 50350.5 mm; GrossFloorArea: 139.284 m2; GrossVolume: 428.994 m3
ID 데이터 - 바닥 마감: T32 테라조타일; 번호: 292; 베이스 마감: PVC 걸레받이; 벽 마감: 수성페인트; 이름: 사무실; 천장 마감: T6무석면택스마감
공정 - 공정: 새 구성
구속조건 - 베이스 간격띄우기: 0 mm; 상한값: 지상 9층; 레벨: 지상 9층; 한계 간격띄우기: 3080 mm
기타 - 공정 ID: 0; 카테고리: 룸; 거실여부: yes; 공간분류코드: 33606; 실ID: 903
에너지 해석 - 구역별 실제 전력 부하: 0; 구역별 실제 조명 부하: 0; 기초 전력 부하: 공간 유형별; 기초 조명 부하: 공간 유형별; 사람 수: 0; 열 부하 값: 공간 유형별; 전력 부하 단위: 전력 밀도; 조명 부하 단위: 전력 밀도; 1인당 잠열 취득: 58.6142 W; 1인당 현열 취득: 73.2678 W; 개인별 면적: 28.5714 m2; 실제 전력 부하: 0 W; 실제 조명 부하: 0 W; 지정된 구역별 전력 부하: 13.9931; 지정된 구역별 조명 부하: 10.7639; 지정된 전력 부하: 0 W; 지정된 조명 부하: 0 W; 천장속 조명 방사: 20; 총 개인별 열 취득: 131.882 W
치수 - 계산 높이: 1000 mm; 둘레: 49442.2 mm; 면적: 139.284 m2; 무한한 높이: 3080 mm; 체적: 428.994 m3

# IfcSpace: 사무실 2:3691753, 2
In: 지상 3층
LongName: 사무실; InteriorOrExteriorSpace: INTERNAL
Pset_SpaceCommon - Reference: 사무실 2; FloorCovering: T32 테라조타일; WallCovering: 수성페인트; CeilingCovering: T6무석면택스마감
BaseQuantities - NetFloorArea: 106.588 m2; Height: 2980 mm; GrossPerimeter: 43121.7 mm; GrossFloorArea: 106.588 m2; GrossVolume: 317.633 m3
ID 데이터 - 바닥 마감: T32 테라조타일; 번호: 2; 베이스 마감: PVC 걸레받이; 벽 마감: 수성페인트; 이름: 사무실; 천장 마감: T6무석면택스마감
공정 - 공정: 새 구성
구속조건 - 베이스 간격띄우기: 0 mm; 상한값: 지상 3층; 레벨: 지상 3층; 한계 간격띄우기: 2980 mm
기타 - 공정 ID: 0; 카테고리: 룸; 거실여부: yes; 방화구획: yes; 공간분류코드: 33606; 실ID: 302
에너지 해석 - 구역별 실제 전력 부하: 0; 구역별 실제 조명 부하: 0; 기초 전력 부하: 공간 유형별; 기초 조명 부하: 공간 유형별; 사람 수: 0; 열 부하 값: 공간 유형별; 전력 부하 단위: 전력 밀도; 조명 부하 단위: 전력 밀도; 1인당 잠열 취득: 58.6142 W; 1인당 현열 취득: 73.2678 W; 개인별 면적: 28.5714 m2; 실제 전력 부하: 0 W; 실제 조명 부하: 0 W; 지정된 구역별 전력 부하: 13.9931; 지정된 구역별 조명 부하: 10.7639; 지정된 전력 부하: 0 W; 지정된 조명 부하: 0 W; 천장속 조명 방사: 20; 총 개인별 열 취득: 131.882 W
치수 - 계산 높이: 1000 mm; 둘레: 42648.2 mm; 면적: 106.588 m2; 무한한 높이: 2980 mm; 체적: 317.633 m3

# IfcSpace: 사무실 301:3694891, 301
In: 지상 10층
LongName: 사무실; InteriorOrExteriorSpace: INTERNAL
Pset_SpaceCommon - Reference: 사무실 301; FloorCovering: T32 테라조타일; WallCovering: 수성페인트; CeilingCovering: T6무석면택스마감
BaseQuantities - NetFloorArea: 77.4151 m2; Height: 3580 mm; GrossFloorArea: 77.4151 m2; GrossVolume: 277.146 m3
ID 데이터 - 바닥 마감: T32 테라조타일; 번호: 301; 베이스 마감: PVC 걸레받이; 벽 마감: 수성페인트; 이름: 사무실; 천장 마감: T6무석면택스마감
공정 - 공정: 새 구성
구속조건 - 베이스 간격띄우기: 0 mm; 레벨: 지상 10층; 상한값: 지상 10층; 한계 간격띄우기: 3580 mm
기타 - 공정 ID: 0; 카테고리: 룸; 거실여부: yes; 공간분류코드: 33606; 실ID: 1001
에너지 해석 - 구역별 실제 전력 부하: 0; 구역별 실제 조명 부하: 0; 기초 전력 부하: 공간 유형별; 기초 조명 부하: 공간 유형별; 사람 수: 0; 열 부하 값: 공간 유형별; 전력 부하 단위: 전력 밀도; 조명 부하 단위: 전력 밀도; 1인당 잠열 취득: 58.6142 W; 1인당 현열 취득: 73.2678 W; 개인별 면적: 28.5714 m2; 실제 전력 부하: 0 W; 실제 조명 부하: 0 W; 지정된 구역별 전력 부하: 13.9931; 지정된 구역별 조명 부하: 10.7639; 지정된 전력 부하: 0 W; 지정된 조명 부하: 0 W; 천장속 조명 방사: 20; 총 개인별 열 취득: 131.882 W
치수 - 계산 높이: 1000 mm; 둘레: 42024.7 mm; 면적: 77.4151 m2; 무한한 높이: 3580 mm; 체적: 270.982 m3

# IfcSpace: 사무실 303:3694898, 303
In: 지상 10층
LongName: 사무실; InteriorOrExteriorSpace: INTERNAL
Pset_SpaceCommon - Reference: 사무실 303; FloorCovering: T32 테라조타일; WallCovering: 수성페인트; CeilingCovering: T6무석면택스마감
BaseQuantities - NetFloorArea: 86.0167 m2; Height: 3580 mm; GrossFloorArea: 86.0167 m2; GrossVolume: 307.94 m3
ID 데이터 - 바닥 마감: T32 테라조타일; 번호: 303; 베이스 마감: PVC 걸레받이; 벽 마감: 수성페인트; 이름: 사무실; 천장 마감: T6무석면택스마감
공정 - 공정: 새 구성
구속조건 - 베이스 간격띄우기: 0 mm; 상한값: 지상 10층; 레벨: 지상 10층; 한계 간격띄우기: 3580 mm
기타 - 공정 ID: 0; 카테고리: 룸; 거실여부: yes; 공간분류코드: 33606; 실ID: 1002
에너지 해석 - 구역별 실제 전력 부하: 0; 구역별 실제 조명 부하: 0; 기초 전력 부하: 공간 유형별; 기초 조명 부하: 공간 유형별; 사람 수: 0; 열 부하 값: 공간 유형별; 전력 부하 단위: 전력 밀도; 조명 부하 단위: 전력 밀도; 1인당 잠열 취득: 58.6142 W; 1인당 현열 취득: 73.2678 W; 개인별 면적: 28.5714 m2; 실제 전력 부하: 0 W; 실제 조명 부하: 0 W; 지정된 구역별 전력 부하: 13.9931; 지정된 구역별 조명 부하: 10.7639; 지정된 전력 부하: 0 W; 지정된 조명 부하: 0 W; 천장속 조명 방사: 20; 총 개인별 열 취득: 131.882 W
치수 - 계산 높이: 1000 mm; 둘레: 39401.4 mm; 면적: 86.0167 m2; 무한한 높이: 3580 mm; 체적: 301.084 m3

# IfcSpace: 사무실 307:3694910, 307
In: 지상 10층
LongName: 사무실; InteriorOrExteriorSpace: INTERNAL
Pset_SpaceCommon - Reference: 사무실 307; FloorCovering: T32 테라조타일; WallCovering: 수성페인트; CeilingCovering: T6무석면택스마감
BaseQuantities - NetFloorArea: 139.436 m2; Height: 3580 mm; GrossFloorArea: 139.436 m2; GrossVolume: 499.18 m3
ID 데이터 - 바닥 마감: T32 테라조타일; 번호: 307; 베이스 마감: PVC 걸레받이; 벽 마감: 수성페인트; 이름: 사무실; 천장 마감: T6무석면택스마감
공정 - 공정: 새 구성
구속조건 - 베이스 간격띄우기: 0 mm; 상한값: 지상 10층; 레벨: 지상 10층; 한계 간격띄우기: 3580 mm
기타 - 공정 ID: 0; 카테고리: 룸; 거실여부: yes; 공간분류코드: 33606; 실ID: 1003
에너지 해석 - 구역별 실제 전력 부하: 0; 구역별 실제 조명 부하: 0; 기초 전력 부하: 공간 유형별; 기초 조명 부하: 공간 유형별; 사람 수: 0; 열 부하 값: 공간 유형별; 전력 부하 단위: 전력 밀도; 조명 부하 단위: 전력 밀도; 1인당 잠열 취득: 58.6142 W; 1인당 현열 취득: 73.2678 W; 개인별 면적: 28.5714 m2; 실제 전력 부하: 0 W; 실제 조명 부하: 0 W; 지정된 구역별 전력 부하: 13.9931; 지정된 구역별 조명 부하: 10.7639; 지정된 전력 부하: 0 W; 지정된 조명 부하: 0 W; 천장속 조명 방사: 20; 총 개인별 열 취득: 131.882 W
치수 - 계산 높이: 1000 mm; 둘레: 49874.8 mm; 면적: 139.436 m2; 무한한 높이: 3580 mm; 체적: 488.074 m3

# IfcSpace: 사무실 317:3695522, 317
In: 지상 4층
LongName: 사무실; InteriorOrExteriorSpace: INTERNAL
Pset_SpaceCommon - Reference: 사무실 317; FloorCovering: T32 테라조타일; WallCovering: 수성페인트; CeilingCovering: T6무석면택스마감
BaseQuantities - NetFloorArea: 85.7288 m2; Height: 2980 mm; GrossPerimeter: 39587 mm; GrossFloorArea: 85.7288 m2; GrossVolume: 255.472 m3
ID 데이터 - 바닥 마감: T32 테라조타일; 번호: 317; 베이스 마감: 목재 걸레받이; 벽 마감: 수성페인트; 이름: 사무실; 천장 마감: T6무석면택스마감
공정 - 공정: 새 구성
구속조건 - 베이스 간격띄우기: 0 mm; 상한값: 지상 4층; 레벨: 지상 4층; 한계 간격띄우기: 2980 mm
기타 - 공정 ID: 0; 카테고리: 룸; 거실여부: yes; 공간분류코드: 33606; 실ID: 419
에너지 해석 - 구역별 실제 전력 부하: 0; 구역별 실제 조명 부하: 0; 기초 전력 부하: 공간 유형별; 기초 조명 부하: 공간 유형별; 사람 수: 0; 열 부하 값: 공간 유형별; 전력 부하 단위: 전력 밀도; 조명 부하 단위: 전력 밀도; 1인당 잠열 취득: 58.6142 W; 1인당 현열 취득: 73.2678 W; 개인별 면적: 28.5714 m2; 실제 전력 부하: 0 W; 실제 조명 부하: 0 W; 지정된 구역별 전력 부하: 13.9931; 지정된 구역별 조명 부하: 10.7639; 지정된 전력 부하: 0 W; 지정된 조명 부하: 0 W; 천장속 조명 방사: 20; 총 개인별 열 취득: 131.882 W
치수 - 계산 높이: 1000 mm; 둘레: 39587 mm; 면적: 85.7288 m2; 무한한 높이: 2980 mm; 체적: 255.472 m3

# IfcSpace: 사무실 3:3691756, 3
In: 지상 3층
LongName: 사무실; InteriorOrExteriorSpace: INTERNAL
Pset_SpaceCommon - Reference: 사무실 3; FloorCovering: T32 테라조타일; WallCovering: 수성페인트; CeilingCovering: T6무석면택스마감
BaseQuantities - NetFloorArea: 86.0449 m2; Height: 2980 mm; GrossPerimeter: 39685.7 mm; GrossFloorArea: 86.0449 m2; GrossVolume: 256.414 m3
ID 데이터 - 바닥 마감: T32 테라조타일; 번호: 3; 베이스 마감: PVC 걸레받이; 벽 마감: 수성페인트; 이름: 사무실; 천장 마감: T6무석면택스마감
공정 - 공정: 새 구성
구속조건 - 베이스 간격띄우기: 0 mm; 상한값: 지상 3층; 레벨: 지상 3층; 한계 간격띄우기: 2980 mm
기타 - 공정 ID: 0; 카테고리: 룸; 거실여부: yes; 방화구획: yes; 공간분류코드: 33606; 실ID: 303
에너지 해석 - 구역별 실제 전력 부하: 0; 구역별 실제 조명 부하: 0; 기초 전력 부하: 공간 유형별; 기초 조명 부하: 공간 유형별; 사람 수: 0; 열 부하 값: 공간 유형별; 전력 부하 단위: 전력 밀도; 조명 부하 단위: 전력 밀도; 1인당 잠열 취득: 58.6142 W; 1인당 현열 취득: 73.2678 W; 개인별 면적: 28.5714 m2; 실제 전력 부하: 0 W; 실제 조명 부하: 0 W; 지정된 구역별 전력 부하: 13.9931; 지정된 구역별 조명 부하: 10.7639; 지정된 전력 부하: 0 W; 지정된 조명 부하: 0 W; 천장속 조명 방사: 20; 총 개인별 열 취득: 131.882 W
치수 - 계산 높이: 1000 mm; 둘레: 39212.2 mm; 면적: 86.0449 m2; 무한한 높이: 2980 mm; 체적: 256.414 m3

# IfcSpace: 사무실 4:3691759, 4
In: 지상 3층
LongName: 사무실; InteriorOrExteriorSpace: INTERNAL
Pset_SpaceCommon - Reference: 사무실 4; FloorCovering: T32 테라조타일; WallCovering: 수성페인트; CeilingCovering: T6무석면택스마감
BaseQuantities - NetFloorArea: 197.145 m2; Height: 2980 mm; GrossPerimeter: 60193.7 mm; GrossFloorArea: 197.145 m2; GrossVolume: 587.491 m3
ID 데이터 - 바닥 마감: T32 테라조타일; 번호: 4; 베이스 마감: PVC 걸레받이; 벽 마감: 수성페인트; 이름: 사무실; 천장 마감: T6무석면택스마감
공정 - 공정: 새 구성
구속조건 - 베이스 간격띄우기: 0 mm; 상한값: 지상 3층; 레벨: 지상 3층; 한계 간격띄우기: 2980 mm
기타 - 공정 ID: 0; 카테고리: 룸; 거실여부: yes; 방화구획: yes; 공간분류코드: 33606; 실ID: 304
에너지 해석 - 구역별 실제 전력 부하: 0; 구역별 실제 조명 부하: 0; 기초 전력 부하: 공간 유형별; 기초 조명 부하: 공간 유형별; 사람 수: 0; 열 부하 값: 공간 유형별; 전력 부하 단위: 전력 밀도; 조명 부하 단위: 전력 밀도; 1인당 잠열 취득: 58.6142 W; 1인당 현열 취득: 73.2678 W; 개인별 면적: 28.5714 m2; 실제 전력 부하: 0 W; 실제 조명 부하: 0 W; 지정된 구역별 전력 부하: 13.9931; 지정된 구역별 조명 부하: 10.7639; 지정된 전력 부하: 0 W; 지정된 조명 부하: 0 W; 천장속 조명 방사: 20; 총 개인별 열 취득: 131.882 W
치수 - 계산 높이: 1000 mm; 둘레: 58755 mm; 면적: 197.145 m2; 무한한 높이: 2980 mm; 체적: 587.491 m3

# IfcSpace: 사무실 5:3691762, 5
In: 지상 3층
LongName: 사무실; InteriorOrExteriorSpace: INTERNAL
Pset_SpaceCommon - Reference: 사무실 5; FloorCovering: T32 테라조타일; WallCovering: 수성페인트; CeilingCovering: T6무석면택스마감
BaseQuantities - NetFloorArea: 130.74 m2; Height: 2980 mm; GrossPerimeter: 46087 mm; GrossFloorArea: 130.74 m2; GrossVolume: 389.606 m3
ID 데이터 - 바닥 마감: T32 테라조타일; 번호: 5; 베이스 마감: PVC 걸레받이; 벽 마감: 수성페인트; 이름: 사무실; 천장 마감: T6무석면택스마감
공정 - 공정: 새 구성
구속조건 - 베이스 간격띄우기: 0 mm; 상한값: 지상 3층; 레벨: 지상 3층; 한계 간격띄우기: 2980 mm
기타 - 공정 ID: 0; 카테고리: 룸; 거실여부: yes; 방화구획: yes; 공간분류코드: 33606; 실ID: 305
에너지 해석 - 구역별 실제 전력 부하: 0; 구역별 실제 조명 부하: 0; 기초 전력 부하: 공간 유형별; 기초 조명 부하: 공간 유형별; 사람 수: 0; 열 부하 값: 공간 유형별; 전력 부하 단위: 전력 밀도; 조명 부하 단위: 전력 밀도; 1인당 잠열 취득: 58.6142 W; 1인당 현열 취득: 73.2678 W; 개인별 면적: 28.5714 m2; 실제 전력 부하: 0 W; 실제 조명 부하: 0 W; 지정된 구역별 전력 부하: 13.9931; 지정된 구역별 조명 부하: 10.7639; 지정된 전력 부하: 0 W; 지정된 조명 부하: 0 W; 천장속 조명 방사: 20; 총 개인별 열 취득: 131.882 W
치수 - 계산 높이: 1000 mm; 둘레: 45613.4 mm; 면적: 130.74 m2; 무한한 높이: 2980 mm; 체적: 389.606 m3

# IfcSpace: 사무실 6:3691765, 6
In: 지상 3층
LongName: 사무실; InteriorOrExteriorSpace: INTERNAL
Pset_SpaceCommon - Reference: 사무실 6; FloorCovering: T32 테라조타일; WallCovering: 수성페인트; CeilingCovering: T6무석면택스마감
BaseQuantities - NetFloorArea: 149.482 m2; Height: 2980 mm; GrossPerimeter: 52930.4 mm; GrossFloorArea: 149.482 m2; GrossVolume: 445.456 m3
ID 데이터 - 바닥 마감: T32 테라조타일; 번호: 6; 베이스 마감: PVC 걸레받이; 벽 마감: 수성페인트; 이름: 사무실; 천장 마감: T6무석면택스마감
공정 - 공정: 새 구성
구속조건 - 베이스 간격띄우기: 0 mm; 상한값: 지상 3층; 레벨: 지상 3층; 한계 간격띄우기: 2980 mm
기타 - 공정 ID: 0; 카테고리: 룸; 거실여부: yes; 방화구획: yes; 공간분류코드: 33606; 실ID: 306
에너지 해석 - 구역별 실제 전력 부하: 0; 구역별 실제 조명 부하: 0; 기초 전력 부하: 공간 유형별; 기초 조명 부하: 공간 유형별; 사람 수: 0; 열 부하 값: 공간 유형별; 전력 부하 단위: 전력 밀도; 조명 부하 단위: 전력 밀도; 1인당 잠열 취득: 58.6142 W; 1인당 현열 취득: 73.2678 W; 개인별 면적: 28.5714 m2; 실제 전력 부하: 0 W; 실제 조명 부하: 0 W; 지정된 구역별 전력 부하: 13.9931; 지정된 구역별 조명 부하: 10.7639; 지정된 전력 부하: 0 W; 지정된 조명 부하: 0 W; 천장속 조명 방사: 20; 총 개인별 열 취득: 131.882 W
치수 - 계산 높이: 1000 mm; 둘레: 52035.8 mm; 면적: 149.482 m2; 무한한 높이: 2980 mm; 체적: 445.456 m3

# IfcSpace: 사무실 7:3691768, 7
In: 지상 3층
LongName: 사무실; InteriorOrExteriorSpace: INTERNAL
Pset_SpaceCommon - Reference: 사무실 7; FloorCovering: T32 테라조타일; WallCovering: 수성페인트; CeilingCovering: T6무석면택스마감
BaseQuantities - NetFloorArea: 137.994 m2; Height: 2980 mm; GrossPerimeter: 50491.6 mm; GrossFloorArea: 137.994 m2; GrossVolume: 411.223 m3
ID 데이터 - 바닥 마감: T32 테라조타일; 번호: 7; 베이스 마감: PVC 걸레받이; 벽 마감: 수성페인트; 이름: 사무실; 천장 마감: T6무석면택스마감
공정 - 공정: 새 구성
구속조건 - 베이스 간격띄우기: 0 mm; 상한값: 지상 3층; 레벨: 지상 3층; 한계 간격띄우기: 2980 mm
기타 - 공정 ID: 0; 카테고리: 룸; 거실여부: yes; 방화구획: yes; 공간분류코드: 33606; 실ID: 307
에너지 해석 - 구역별 실제 전력 부하: 0; 구역별 실제 조명 부하: 0; 기초 전력 부하: 공간 유형별; 기초 조명 부하: 공간 유형별; 사람 수: 0; 열 부하 값: 공간 유형별; 전력 부하 단위: 전력 밀도; 조명 부하 단위: 전력 밀도; 1인당 잠열 취득: 58.6142 W; 1인당 현열 취득: 73.2678 W; 개인별 면적: 28.5714 m2; 실제 전력 부하: 0 W; 실제 조명 부하: 0 W; 지정된 구역별 전력 부하: 13.9931; 지정된 구역별 조명 부하: 10.7639; 지정된 전력 부하: 0 W; 지정된 조명 부하: 0 W; 천장속 조명 방사: 20; 총 개인별 열 취득: 131.882 W
치수 - 계산 높이: 1000 mm; 둘레: 50293.5 mm; 면적: 137.994 m2; 무한한 높이: 2980 mm; 체적: 411.223 m3

# IfcSpace: 사무실 90:6517365, 90
In: 지상 8층
LongName: 사무실; InteriorOrExteriorSpace: INTERNAL
Pset_SpaceCommon - Reference: 사무실 90; FloorCovering: T32 테라조타일; WallCovering: 수성페인트; CeilingCovering: T6무석면택스마감
BaseQuantities - NetFloorArea: 196.793 m2; Height: 2980 mm; GrossPerimeter: 59524.3 mm; GrossFloorArea: 196.793 m2; GrossVolume: 586.444 m3
ID 데이터 - 바닥 마감: T32 테라조타일; 번호: 90; 베이스 마감: PVC 걸레받이; 벽 마감: 수성페인트; 이름: 사무실; 천장 마감: T6무석면택스마감
공정 - 공정: 새 구성
구속조건 - 베이스 간격띄우기: 0 mm; 상한값: 지상 8층; 레벨: 지상 8층; 한계 간격띄우기: 2980 mm
기타 - 공정 ID: 0; 카테고리: 룸; 거실여부: yes; 공간분류코드: 33606; 실ID: 816
에너지 해석 - 구역별 실제 전력 부하: 0; 구역별 실제 조명 부하: 0; 기초 전력 부하: 공간 유형별; 기초 조명 부하: 공간 유형별; 사람 수: 0; 열 부하 값: 공간 유형별; 전력 부하 단위: 전력 밀도; 조명 부하 단위: 전력 밀도; 1인당 잠열 취득: 58.6142 W; 1인당 현열 취득: 73.2678 W; 개인별 면적: 28.5714 m2; 실제 전력 부하: 0 W; 실제 조명 부하: 0 W; 지정된 구역별 전력 부하: 13.9931; 지정된 구역별 조명 부하: 10.7639; 지정된 전력 부하: 0 W; 지정된 조명 부하: 0 W; 천장속 조명 방사: 20; 총 개인별 열 취득: 131.882 W
치수 - 계산 높이: 1000 mm; 둘레: 59041.7 mm; 면적: 196.793 m2; 무한한 높이: 2980 mm; 체적: 586.444 m3

# IfcSpace: 사무실 91:6517525, 91
In: 지상 8층
LongName: 사무실; InteriorOrExteriorSpace: INTERNAL
Pset_SpaceCommon - Reference: 사무실 91; FloorCovering: T32 테라조타일; WallCovering: 수성페인트; CeilingCovering: T6무석면택스마감
BaseQuantities - NetFloorArea: 130.527 m2; Height: 2980 mm; GrossPerimeter: 45987 mm; GrossFloorArea: 130.527 m2; GrossVolume: 388.97 m3
ID 데이터 - 바닥 마감: T32 테라조타일; 번호: 91; 베이스 마감: PVC 걸레받이; 벽 마감: 수성페인트; 이름: 사무실; 천장 마감: T6무석면택스마감
공정 - 공정: 새 구성
구속조건 - 베이스 간격띄우기: 0 mm; 상한값: 지상 8층; 레벨: 지상 8층; 한계 간격띄우기: 2980 mm
기타 - 공정 ID: 0; 카테고리: 룸; 거실여부: yes; 공간분류코드: 33606; 실ID: 817
에너지 해석 - 구역별 실제 전력 부하: 0; 구역별 실제 조명 부하: 0; 기초 전력 부하: 공간 유형별; 기초 조명 부하: 공간 유형별; 사람 수: 0; 열 부하 값: 공간 유형별; 전력 부하 단위: 전력 밀도; 조명 부하 단위: 전력 밀도; 1인당 잠열 취득: 58.6142 W; 1인당 현열 취득: 73.2678 W; 개인별 면적: 28.5714 m2; 실제 전력 부하: 0 W; 실제 조명 부하: 0 W; 지정된 구역별 전력 부하: 13.9931; 지정된 구역별 조명 부하: 10.7639; 지정된 전력 부하: 0 W; 지정된 조명 부하: 0 W; 천장속 조명 방사: 20; 총 개인별 열 취득: 131.882 W
치수 - 계산 높이: 1000 mm; 둘레: 45987 mm; 면적: 130.527 m2; 무한한 높이: 2980 mm; 체적: 388.97 m3

# IfcSpace: 사무실 92:6517579, 92
In: 지상 8층
LongName: 사무실; InteriorOrExteriorSpace: INTERNAL
Pset_SpaceCommon - Reference: 사무실 92; FloorCovering: T32 테라조타일; WallCovering: 수성페인트; CeilingCovering: T6무석면택스마감
BaseQuantities - NetFloorArea: 150.382 m2; Height: 2980 mm; GrossPerimeter: 52858 mm; GrossFloorArea: 150.382 m2; GrossVolume: 448.139 m3
ID 데이터 - 바닥 마감: T32 테라조타일; 번호: 92; 베이스 마감: PVC 걸레받이; 벽 마감: 수성페인트; 이름: 사무실; 천장 마감: T6무석면택스마감
공정 - 공정: 새 구성
구속조건 - 베이스 간격띄우기: 0 mm; 상한값: 지상 8층; 레벨: 지상 8층; 한계 간격띄우기: 2980 mm
기타 - 공정 ID: 0; 카테고리: 룸; 거실여부: yes; 공간분류코드: 33606; 실ID: 818
에너지 해석 - 구역별 실제 전력 부하: 0; 구역별 실제 조명 부하: 0; 기초 전력 부하: 공간 유형별; 기초 조명 부하: 공간 유형별; 사람 수: 0; 열 부하 값: 공간 유형별; 전력 부하 단위: 전력 밀도; 조명 부하 단위: 전력 밀도; 1인당 잠열 취득: 58.6142 W; 1인당 현열 취득: 73.2678 W; 개인별 면적: 28.5714 m2; 실제 전력 부하: 0 W; 실제 조명 부하: 0 W; 지정된 구역별 전력 부하: 13.9931; 지정된 구역별 조명 부하: 10.7639; 지정된 전력 부하: 0 W; 지정된 조명 부하: 0 W; 천장속 조명 방사: 20; 총 개인별 열 취득: 131.882 W
치수 - 계산 높이: 1000 mm; 둘레: 51933.4 mm; 면적: 150.382 m2; 무한한 높이: 2980 mm; 체적: 448.139 m3

# IfcSpace: 사무실 93:6517646, 93
In: 지상 9층
LongName: 사무실; InteriorOrExteriorSpace: INTERNAL
Pset_SpaceCommon - Reference: 사무실 93; FloorCovering: T32 테라조타일; WallCovering: 수성페인트; CeilingCovering: T6무석면택스마감
BaseQuantities - NetFloorArea: 196.793 m2; Height: 3080 mm; GrossPerimeter: 59524.2 mm; GrossFloorArea: 196.793 m2; GrossVolume: 606.123 m3
ID 데이터 - 바닥 마감: T32 테라조타일; 번호: 93; 베이스 마감: PVC 걸레받이; 벽 마감: 수성페인트; 이름: 사무실; 천장 마감: T6무석면택스마감
공정 - 공정: 새 구성
구속조건 - 베이스 간격띄우기: 0 mm; 상한값: 지상 9층; 레벨: 지상 9층; 한계 간격띄우기: 3080 mm
기타 - 공정 ID: 0; 카테고리: 룸; 거실여부: yes; 공간분류코드: 33606; 실ID: 916
에너지 해석 - 구역별 실제 전력 부하: 0; 구역별 실제 조명 부하: 0; 기초 전력 부하: 공간 유형별; 기초 조명 부하: 공간 유형별; 사람 수: 0; 열 부하 값: 공간 유형별; 전력 부하 단위: 전력 밀도; 조명 부하 단위: 전력 밀도; 1인당 잠열 취득: 58.6142 W; 1인당 현열 취득: 73.2678 W; 개인별 면적: 28.5714 m2; 실제 전력 부하: 0 W; 실제 조명 부하: 0 W; 지정된 구역별 전력 부하: 13.9931; 지정된 구역별 조명 부하: 10.7639; 지정된 전력 부하: 0 W; 지정된 조명 부하: 0 W; 천장속 조명 방사: 20; 총 개인별 열 취득: 131.882 W
치수 - 계산 높이: 1000 mm; 둘레: 59032.7 mm; 면적: 196.793 m2; 무한한 높이: 3080 mm; 체적: 606.123 m3

# IfcSpace: 사무실 94:6517690, 94
In: 지상 9층
LongName: 사무실; InteriorOrExteriorSpace: INTERNAL
Pset_SpaceCommon - Reference: 사무실 94; FloorCovering: T32 테라조타일; WallCovering: 수성페인트; CeilingCovering: T6무석면택스마감
BaseQuantities - NetFloorArea: 130.527 m2; Height: 3080 mm; GrossPerimeter: 45987 mm; GrossFloorArea: 130.527 m2; GrossVolume: 402.024 m3
ID 데이터 - 바닥 마감: T32 테라조타일; 번호: 94; 베이스 마감: PVC 걸레받이; 벽 마감: 수성페인트; 이름: 사무실; 천장 마감: T6무석면택스마감
공정 - 공정: 새 구성
구속조건 - 베이스 간격띄우기: 0 mm; 상한값: 지상 9층; 레벨: 지상 9층; 한계 간격띄우기: 3080 mm
기타 - 공정 ID: 0; 카테고리: 룸; 거실여부: yes; 공간분류코드: 33606; 실ID: 917
에너지 해석 - 구역별 실제 전력 부하: 0; 구역별 실제 조명 부하: 0; 기초 전력 부하: 공간 유형별; 기초 조명 부하: 공간 유형별; 사람 수: 0; 열 부하 값: 공간 유형별; 전력 부하 단위: 전력 밀도; 조명 부하 단위: 전력 밀도; 1인당 잠열 취득: 58.6142 W; 1인당 현열 취득: 73.2678 W; 개인별 면적: 28.5714 m2; 실제 전력 부하: 0 W; 실제 조명 부하: 0 W; 지정된 구역별 전력 부하: 13.9931; 지정된 구역별 조명 부하: 10.7639; 지정된 전력 부하: 0 W; 지정된 조명 부하: 0 W; 천장속 조명 방사: 20; 총 개인별 열 취득: 131.882 W
치수 - 계산 높이: 1000 mm; 둘레: 45969 mm; 면적: 130.527 m2; 무한한 높이: 3080 mm; 체적: 402.024 m3

# IfcSpace: 사무실 95:6517710, 95
In: 지상 9층
LongName: 사무실; InteriorOrExteriorSpace: INTERNAL
Pset_SpaceCommon - Reference: 사무실 95; FloorCovering: T32 테라조타일; WallCovering: 수성페인트; CeilingCovering: T6무석면택스마감
BaseQuantities - NetFloorArea: 150.384 m2; Height: 3080 mm; GrossPerimeter: 52858 mm; GrossFloorArea: 150.384 m2; GrossVolume: 463.182 m3
ID 데이터 - 바닥 마감: T32 테라조타일; 번호: 95; 베이스 마감: PVC 걸레받이; 벽 마감: 수성페인트; 이름: 사무실; 천장 마감: T6무석면택스마감
공정 - 공정: 새 구성
구속조건 - 베이스 간격띄우기: 0 mm; 상한값: 지상 9층; 레벨: 지상 9층; 한계 간격띄우기: 3080 mm
기타 - 공정 ID: 0; 카테고리: 룸; 거실여부: yes; 공간분류코드: 33606; 실ID: 918
에너지 해석 - 구역별 실제 전력 부하: 0; 구역별 실제 조명 부하: 0; 기초 전력 부하: 공간 유형별; 기초 조명 부하: 공간 유형별; 사람 수: 0; 열 부하 값: 공간 유형별; 전력 부하 단위: 전력 밀도; 조명 부하 단위: 전력 밀도; 1인당 잠열 취득: 58.6142 W; 1인당 현열 취득: 73.2678 W; 개인별 면적: 28.5714 m2; 실제 전력 부하: 0 W; 실제 조명 부하: 0 W; 지정된 구역별 전력 부하: 13.9931; 지정된 구역별 조명 부하: 10.7639; 지정된 전력 부하: 0 W; 지정된 조명 부하: 0 W; 천장속 조명 방사: 20; 총 개인별 열 취득: 131.882 W
치수 - 계산 높이: 1000 mm; 둘레: 51938.4 mm; 면적: 150.384 m2; 무한한 높이: 3080 mm; 체적: 463.182 m3

# IfcSpace: 사무실 96:6517755, 96
In: 지상 10층
LongName: 사무실; InteriorOrExteriorSpace: INTERNAL
Pset_SpaceCommon - Reference: 사무실 96; FloorCovering: T32 테라조타일; WallCovering: 수성페인트; CeilingCovering: T6무석면택스마감
BaseQuantities - NetFloorArea: 197.848 m2; Height: 3580 mm; GrossFloorArea: 197.848 m2; GrossVolume: 708.297 m3
ID 데이터 - 바닥 마감: T32 테라조타일; 번호: 96; 베이스 마감: PVC 걸레받이; 벽 마감: 수성페인트; 이름: 사무실; 천장 마감: T6무석면택스마감
공정 - 공정: 새 구성
구속조건 - 베이스 간격띄우기: 0 mm; 상한값: 지상 10층; 레벨: 지상 10층; 한계 간격띄우기: 3580 mm
기타 - 공정 ID: 0; 카테고리: 룸; 거실여부: yes; 공간분류코드: 33606; 실ID: 1011
에너지 해석 - 구역별 실제 전력 부하: 0; 구역별 실제 조명 부하: 0; 기초 전력 부하: 공간 유형별; 기초 조명 부하: 공간 유형별; 사람 수: 0; 열 부하 값: 공간 유형별; 전력 부하 단위: 전력 밀도; 조명 부하 단위: 전력 밀도; 1인당 잠열 취득: 58.6142 W; 1인당 현열 취득: 73.2678 W; 개인별 면적: 28.5714 m2; 실제 전력 부하: 0 W; 실제 조명 부하: 0 W; 지정된 구역별 전력 부하: 13.9931; 지정된 구역별 조명 부하: 10.7639; 지정된 전력 부하: 0 W; 지정된 조명 부하: 0 W; 천장속 조명 방사: 20; 총 개인별 열 취득: 131.882 W
치수 - 계산 높이: 1000 mm; 둘레: 58987.7 mm; 면적: 197.848 m2; 무한한 높이: 3580 mm; 체적: 692.572 m3

# IfcSpace: 사무실 97:6517778, 97
In: 지상 10층
LongName: 사무실; InteriorOrExteriorSpace: INTERNAL
Pset_SpaceCommon - Reference: 사무실 97; FloorCovering: T32 테라조타일; WallCovering: 수성페인트; CeilingCovering: T6무석면택스마감
BaseQuantities - NetFloorArea: 131.032 m2; Height: 3580 mm; GrossFloorArea: 131.032 m2; GrossVolume: 469.094 m3
ID 데이터 - 바닥 마감: T32 테라조타일; 번호: 97; 베이스 마감: PVC 걸레받이; 벽 마감: 수성페인트; 이름: 사무실; 천장 마감: T6무석면택스마감
공정 - 공정: 새 구성
구속조건 - 베이스 간격띄우기: 0 mm; 상한값: 지상 10층; 레벨: 지상 10층; 한계 간격띄우기: 3580 mm
기타 - 공정 ID: 0; 카테고리: 룸; 거실여부: yes; 공간분류코드: 33606; 실ID: 1012
에너지 해석 - 구역별 실제 전력 부하: 0; 구역별 실제 조명 부하: 0; 기초 전력 부하: 공간 유형별; 기초 조명 부하: 공간 유형별; 사람 수: 0; 열 부하 값: 공간 유형별; 전력 부하 단위: 전력 밀도; 조명 부하 단위: 전력 밀도; 1인당 잠열 취득: 58.6142 W; 1인당 현열 취득: 73.2678 W; 개인별 면적: 28.5714 m2; 실제 전력 부하: 0 W; 실제 조명 부하: 0 W; 지정된 구역별 전력 부하: 13.9931; 지정된 구역별 조명 부하: 10.7639; 지정된 전력 부하: 0 W; 지정된 조명 부하: 0 W; 천장속 조명 방사: 20; 총 개인별 열 취득: 131.882 W
치수 - 계산 높이: 1000 mm; 둘레: 45936.5 mm; 면적: 131.032 m2; 무한한 높이: 3580 mm; 체적: 458.651 m3

# IfcSpace: 사무실 98:6517803, 98
In: 지상 10층
LongName: 사무실; InteriorOrExteriorSpace: INTERNAL
Pset_SpaceCommon - Reference: 사무실 98; FloorCovering: T32 테라조타일; WallCovering: 수성페인트; CeilingCovering: T6무석면택스마감
BaseQuantities - NetFloorArea: 150.792 m2; Height: 3580 mm; GrossFloorArea: 150.792 m2; GrossVolume: 539.837 m3
ID 데이터 - 바닥 마감: T32 테라조타일; 번호: 98; 베이스 마감: PVC 걸레받이; 벽 마감: 수성페인트; 이름: 사무실; 천장 마감: T6무석면택스마감
공정 - 공정: 새 구성
구속조건 - 베이스 간격띄우기: 0 mm; 상한값: 지상 10층; 레벨: 지상 10층; 한계 간격띄우기: 3580 mm
기타 - 공정 ID: 0; 카테고리: 룸; 거실여부: yes; 공간분류코드: 33606; 실ID: 1013
에너지 해석 - 구역별 실제 전력 부하: 0; 구역별 실제 조명 부하: 0; 기초 전력 부하: 공간 유형별; 기초 조명 부하: 공간 유형별; 사람 수: 0; 열 부하 값: 공간 유형별; 전력 부하 단위: 전력 밀도; 조명 부하 단위: 전력 밀도; 1인당 잠열 취득: 58.6142 W; 1인당 현열 취득: 73.2678 W; 개인별 면적: 28.5714 m2; 실제 전력 부하: 0 W; 실제 조명 부하: 0 W; 지정된 구역별 전력 부하: 13.9931; 지정된 구역별 조명 부하: 10.7639; 지정된 전력 부하: 0 W; 지정된 조명 부하: 0 W; 천장속 조명 방사: 20; 총 개인별 열 취득: 131.882 W
치수 - 계산 높이: 1000 mm; 둘레: 52214.1 mm; 면적: 150.792 m2; 무한한 높이: 3580 mm; 체적: 527.865 m3

# IfcSpace: 사무실 99:6517836, 99
In: 지상 10층
LongName: 사무실; InteriorOrExteriorSpace: INTERNAL
Pset_SpaceCommon - Reference: 사무실 99; FloorCovering: T32 테라조타일; WallCovering: 수성페인트; CeilingCovering: T6무석면택스마감
BaseQuantities - NetFloorArea: 107.12 m2; Height: 3580 mm; GrossFloorArea: 107.12 m2; GrossVolume: 383.491 m3
ID 데이터 - 바닥 마감: T32 테라조타일; 번호: 99; 베이스 마감: PVC 걸레받이; 벽 마감: 수성페인트; 이름: 사무실; 천장 마감: T6무석면택스마감
공정 - 공정: 새 구성
구속조건 - 베이스 간격띄우기: 0 mm; 상한값: 지상 10층; 레벨: 지상 10층; 한계 간격띄우기: 3580 mm
기타 - 공정 ID: 0; 카테고리: 룸; 거실여부: yes; 공간분류코드: 33606; 실ID: 1014
에너지 해석 - 구역별 실제 전력 부하: 0; 구역별 실제 조명 부하: 0; 기초 전력 부하: 공간 유형별; 기초 조명 부하: 공간 유형별; 사람 수: 0; 열 부하 값: 공간 유형별; 전력 부하 단위: 전력 밀도; 조명 부하 단위: 전력 밀도; 1인당 잠열 취득: 58.6142 W; 1인당 현열 취득: 73.2678 W; 개인별 면적: 28.5714 m2; 실제 전력 부하: 0 W; 실제 조명 부하: 0 W; 지정된 구역별 전력 부하: 13.9931; 지정된 구역별 조명 부하: 10.7639; 지정된 전력 부하: 0 W; 지정된 조명 부하: 0 W; 천장속 조명 방사: 20; 총 개인별 열 취득: 131.882 W
치수 - 계산 높이: 1000 mm; 둘레: 42801.6 mm; 면적: 107.12 m2; 무한한 높이: 3580 mm; 체적: 374.948 m3

# IfcSpace: 사무실1-1 162:3691247, 162
In: 지상 1층
LongName: 사무실1-1; InteriorOrExteriorSpace: INTERNAL
Pset_SpaceCommon - Reference: 사무실1-1 162; FloorCovering: T32 테라조타일; WallCovering: 수성페인트; CeilingCovering: T6무석면택스마감
BaseQuantities - NetFloorArea: 42.4893 m2; Height: 5080 mm; GrossPerimeter: 28919 mm; GrossFloorArea: 42.4893 m2; GrossVolume: 215.846 m3
ID 데이터 - 바닥 마감: T32 테라조타일; 번호: 162; 베이스 마감: PVC 걸레받이; 벽 마감: 수성페인트; 이름: 사무실1-1; 천장 마감: T6무석면택스마감
공정 - 공정: 새 구성
구속조건 - 상한값: 지상 1층; 레벨: 지상 1층; 베이스 간격띄우기: -1500 mm; 한계 간격띄우기: 3580 mm
기타 - 공정 ID: 0; 카테고리: 룸; 거실여부: yes; 방화구획: yes; 공간분류코드: 33606; 실ID: 114
에너지 해석 - 구역별 실제 전력 부하: 0; 구역별 실제 조명 부하: 0; 기초 전력 부하: 공간 유형별; 기초 조명 부하: 공간 유형별; 사람 수: 0; 열 부하 값: 공간 유형별; 전력 부하 단위: 전력 밀도; 조명 부하 단위: 전력 밀도; 1인당 잠열 취득: 58.6142 W; 1인당 현열 취득: 73.2678 W; 개인별 면적: 28.5714 m2; 실제 전력 부하: 0 W; 실제 조명 부하: 0 W; 지정된 구역별 전력 부하: 13.9931; 지정된 구역별 조명 부하: 10.7639; 지정된 전력 부하: 0 W; 지정된 조명 부하: 0 W; 천장속 조명 방사: 20; 총 개인별 열 취득: 131.882 W
치수 - 계산 높이: 1000 mm; 둘레: 28919 mm; 면적: 42.4893 m2; 무한한 높이: 5080 mm; 체적: 215.846 m3

# IfcSpace: 사무실1-1 163:3691250, 163
In: 지상 1층
LongName: 사무실1-1; InteriorOrExteriorSpace: INTERNAL
Pset_SpaceCommon - Reference: 사무실1-1 163; FloorCovering: T32 테라조타일; WallCovering: 수성페인트; CeilingCovering: T6무석면택스마감
BaseQuantities - NetFloorArea: 44.4371 m2; Height: 5080 mm; GrossPerimeter: 29446.1 mm; GrossFloorArea: 44.4371 m2; GrossVolume: 225.741 m3
ID 데이터 - 바닥 마감: T32 테라조타일; 번호: 163; 베이스 마감: PVC 걸레받이; 벽 마감: 수성페인트; 이름: 사무실1-1; 천장 마감: T6무석면택스마감
공정 - 공정: 새 구성
구속조건 - 상한값: 지상 1층; 레벨: 지상 1층; 베이스 간격띄우기: -1500 mm; 한계 간격띄우기: 3580 mm
기타 - 공정 ID: 0; 카테고리: 룸; 거실여부: yes; 방화구획: yes; 공간분류코드: 33606; 실ID: 115
에너지 해석 - 구역별 실제 전력 부하: 0; 구역별 실제 조명 부하: 0; 기초 전력 부하: 공간 유형별; 기초 조명 부하: 공간 유형별; 사람 수: 0; 열 부하 값: 공간 유형별; 전력 부하 단위: 전력 밀도; 조명 부하 단위: 전력 밀도; 1인당 잠열 취득: 58.6142 W; 1인당 현열 취득: 73.2678 W; 개인별 면적: 28.5714 m2; 실제 전력 부하: 0 W; 실제 조명 부하: 0 W; 지정된 구역별 전력 부하: 13.9931; 지정된 구역별 조명 부하: 10.7639; 지정된 전력 부하: 0 W; 지정된 조명 부하: 0 W; 천장속 조명 방사: 20; 총 개인별 열 취득: 131.882 W
치수 - 계산 높이: 1000 mm; 둘레: 29446.1 mm; 면적: 44.4371 m2; 무한한 높이: 5080 mm; 체적: 225.741 m3

# IfcSpace: 사무실1-2 161:3691244, 161
In: 지상 1층
LongName: 사무실1-2; InteriorOrExteriorSpace: INTERNAL
Pset_SpaceCommon - Reference: 사무실1-2 161; FloorCovering: T32 테라조타일; WallCovering: 수성페인트; CeilingCovering: T6무석면택스마감
BaseQuantities - NetFloorArea: 46.6235 m2; Height: 4080 mm; GrossPerimeter: 29917 mm; GrossFloorArea: 46.6235 m2; GrossVolume: 190.224 m3
ID 데이터 - 바닥 마감: T32 테라조타일; 번호: 161; 베이스 마감: PVC 걸레받이; 벽 마감: 수성페인트; 이름: 사무실1-2; 천장 마감: T6무석면택스마감
공정 - 공정: 새 구성
구속조건 - 상한값: 지상 1층; 레벨: 지상 1층; 베이스 간격띄우기: -500 mm; 한계 간격띄우기: 3580 mm
기타 - 공정 ID: 0; 카테고리: 룸; 거실여부: yes; 방화구획: yes; 공간분류코드: 33606; 실ID: 113
에너지 해석 - 구역별 실제 전력 부하: 0; 구역별 실제 조명 부하: 0; 기초 전력 부하: 공간 유형별; 기초 조명 부하: 공간 유형별; 사람 수: 0; 열 부하 값: 공간 유형별; 전력 부하 단위: 전력 밀도; 조명 부하 단위: 전력 밀도; 1인당 잠열 취득: 58.6142 W; 1인당 현열 취득: 73.2678 W; 개인별 면적: 28.5714 m2; 실제 전력 부하: 0 W; 실제 조명 부하: 0 W; 지정된 구역별 전력 부하: 13.9931; 지정된 구역별 조명 부하: 10.7639; 지정된 전력 부하: 0 W; 지정된 조명 부하: 0 W; 천장속 조명 방사: 20; 총 개인별 열 취득: 131.882 W
치수 - 계산 높이: 1000 mm; 둘레: 29917 mm; 면적: 46.6235 m2; 무한한 높이: 4080 mm; 체적: 190.224 m3

# IfcSpace: 샤프트 11:5255713, 11
In: 지하2층
LongName: 샤프트; InteriorOrExteriorSpace: INTERNAL
Pset_SpaceCommon - Reference: 샤프트 11; FloorCovering: -; WallCovering: -; CeilingCovering: -
BaseQuantities - NetFloorArea: 6.75277 m2; Height: 5800 mm; GrossPerimeter: 14003.7 mm; GrossFloorArea: 6.75277 m2; GrossVolume: 39.1661 m3
ID 데이터 - 바닥 마감: -; 번호: 11; 베이스 마감: -; 벽 마감: -; 이름: 샤프트; 천장 마감: -
공정 - 공정: 새 구성
구속조건 - 상한값: 지하2층; 레벨: 지하2층; 베이스 간격띄우기: -1800 mm; 한계 간격띄우기: 4000 mm
기타 - 거실여부: no; 공정 ID: 0; 카테고리: 룸; 공간분류코드: 33416; 실ID: B215
에너지 해석 - 구역별 실제 전력 부하: 0; 구역별 실제 조명 부하: 0; 기초 전력 부하: 공간 유형별; 기초 조명 부하: 공간 유형별; 사람 수: 0; 열 부하 값: 공간 유형별; 전력 부하 단위: 전력 밀도; 조명 부하 단위: 전력 밀도; 1인당 잠열 취득: 58.6142 W; 1인당 현열 취득: 73.2678 W; 개인별 면적: 28.5714 m2; 실제 전력 부하: 0 W; 실제 조명 부하: 0 W; 지정된 구역별 전력 부하: 13.9931; 지정된 구역별 조명 부하: 10.7639; 지정된 전력 부하: 0 W; 지정된 조명 부하: 0 W; 천장속 조명 방사: 20; 총 개인별 열 취득: 131.882 W
치수 - 계산 높이: 0 mm; 둘레: 14003.7 mm; 면적: 6.75277 m2; 무한한 높이: 5800 mm; 체적: 39.1661 m3

# IfcSpace: 샤프트 16:5255775, 16
In: 지하1층
LongName: 샤프트; InteriorOrExteriorSpace: INTERNAL
Pset_SpaceCommon - Reference: 샤프트 16; FloorCovering: -; WallCovering: -; CeilingCovering: -
BaseQuantities - NetFloorArea: 6.75277 m2; Height: 6100 mm; GrossPerimeter: 14003.7 mm; GrossFloorArea: 6.75277 m2; GrossVolume: 41.1919 m3
ID 데이터 - 바닥 마감: -; 번호: 16; 베이스 마감: -; 벽 마감: -; 이름: 샤프트; 천장 마감: -
공정 - 공정: 새 구성
구속조건 - 베이스 간격띄우기: 0 mm; 상한값: 지하1층; 레벨: 지하1층; 한계 간격띄우기: 6100 mm
기타 - 거실여부: no; 공정 ID: 0; 카테고리: 룸; 공간분류코드: 33416; 실ID: B114
에너지 해석 - 구역별 실제 전력 부하: 0; 구역별 실제 조명 부하: 0; 기초 전력 부하: 공간 유형별; 기초 조명 부하: 공간 유형별; 사람 수: 0; 열 부하 값: 공간 유형별; 전력 부하 단위: 전력 밀도; 조명 부하 단위: 전력 밀도; 1인당 잠열 취득: 58.6142 W; 1인당 현열 취득: 73.2678 W; 개인별 면적: 28.5714 m2; 실제 전력 부하: 0 W; 실제 조명 부하: 0 W; 지정된 구역별 전력 부하: 13.9931; 지정된 구역별 조명 부하: 10.7639; 지정된 전력 부하: 0 W; 지정된 조명 부하: 0 W; 천장속 조명 방사: 20; 총 개인별 열 취득: 131.882 W
치수 - 계산 높이: 0 mm; 둘레: 14003.7 mm; 면적: 6.75277 m2; 무한한 높이: 6100 mm; 체적: 41.1919 m3

# IfcSpace: 샤프트 21:5255856, 21
In: 지상 1층
LongName: 샤프트; InteriorOrExteriorSpace: INTERNAL
Pset_SpaceCommon - Reference: 샤프트 21; FloorCovering: -; WallCovering: -; CeilingCovering: -
BaseQuantities - NetFloorArea: 6.75277 m2; Height: 4800 mm; GrossFloorArea: 6.75277 m2; GrossVolume: 32.4133 m3
ID 데이터 - 바닥 마감: -; 번호: 21; 베이스 마감: -; 벽 마감: -; 이름: 샤프트; 천장 마감: -
공정 - 공정: 새 구성
구속조건 - 베이스 간격띄우기: 0 mm; 상한값: 지상 1층; 레벨: 지상 1층; 한계 간격띄우기: 4800 mm
기타 - 거실여부: no; 공정 ID: 0; 카테고리: 룸; 공간분류코드: 33416; 실ID: 127
에너지 해석 - 구역별 실제 전력 부하: 0; 구역별 실제 조명 부하: 0; 기초 전력 부하: 공간 유형별; 기초 조명 부하: 공간 유형별; 사람 수: 0; 열 부하 값: 공간 유형별; 전력 부하 단위: 전력 밀도; 조명 부하 단위: 전력 밀도; 1인당 잠열 취득: 58.6142 W; 1인당 현열 취득: 73.2678 W; 개인별 면적: 28.5714 m2; 실제 전력 부하: 0 W; 실제 조명 부하: 0 W; 지정된 구역별 전력 부하: 13.9931; 지정된 구역별 조명 부하: 10.7639; 지정된 전력 부하: 0 W; 지정된 조명 부하: 0 W; 천장속 조명 방사: 20; 총 개인별 열 취득: 131.882 W
치수 - 계산 높이: 1000 mm; 둘레: 14003.7 mm; 면적: 6.75277 m2; 무한한 높이: 4800 mm; 체적: 32.4129 m3

# IfcSpace: 샤프트 22:5255864, 22
In: 지상 1층
LongName: 샤프트; InteriorOrExteriorSpace: INTERNAL
Pset_SpaceCommon - Reference: 샤프트 22; FloorCovering: -; WallCovering: -; CeilingCovering: -
BaseQuantities - NetFloorArea: 2.08 m2; Height: 4800 mm; GrossPerimeter: 6800 mm; GrossFloorArea: 2.08 m2; GrossVolume: 9.984 m3
ID 데이터 - 바닥 마감: -; 번호: 22; 베이스 마감: -; 벽 마감: -; 이름: 샤프트; 천장 마감: -
공정 - 공정: 새 구성
구속조건 - 베이스 간격띄우기: 0 mm; 상한값: 지상 1층; 레벨: 지상 1층; 한계 간격띄우기: 4800 mm
기타 - 거실여부: no; 공정 ID: 0; 카테고리: 룸; 공간분류코드: 33416; 실ID: 128
에너지 해석 - 구역별 실제 전력 부하: 0; 구역별 실제 조명 부하: 0; 기초 전력 부하: 공간 유형별; 기초 조명 부하: 공간 유형별; 사람 수: 0; 열 부하 값: 공간 유형별; 전력 부하 단위: 전력 밀도; 조명 부하 단위: 전력 밀도; 1인당 잠열 취득: 58.6142 W; 1인당 현열 취득: 73.2678 W; 개인별 면적: 28.5714 m2; 실제 전력 부하: 0 W; 실제 조명 부하: 0 W; 지정된 구역별 전력 부하: 13.9931; 지정된 구역별 조명 부하: 10.7639; 지정된 전력 부하: 0 W; 지정된 조명 부하: 0 W; 천장속 조명 방사: 20; 총 개인별 열 취득: 131.882 W
치수 - 계산 높이: 1000 mm; 둘레: 6800 mm; 면적: 2.08 m2; 무한한 높이: 4800 mm; 체적: 9.984 m3

# IfcSpace: 샤프트 23:5255888, 23
In: 지상 1층
LongName: 샤프트; InteriorOrExteriorSpace: INTERNAL
Pset_SpaceCommon - Reference: 샤프트 23; FloorCovering: -; WallCovering: -; CeilingCovering: -
BaseQuantities - NetFloorArea: 4.79986 m2; Height: 5350 mm; GrossPerimeter: 8799.97 mm; GrossFloorArea: 4.79986 m2; GrossVolume: 25.6792 m3
ID 데이터 - 바닥 마감: -; 번호: 23; 베이스 마감: -; 벽 마감: -; 이름: 샤프트; 천장 마감: -
공정 - 공정: 새 구성
구속조건 - 상한값: 지상 1층; 레벨: 지상 1층; 베이스 간격띄우기: -550 mm; 한계 간격띄우기: 4800 mm
기타 - 거실여부: no; 공정 ID: 0; 카테고리: 룸; 공간분류코드: 33416; 실ID: 129
에너지 해석 - 구역별 실제 전력 부하: 0; 구역별 실제 조명 부하: 0; 기초 전력 부하: 공간 유형별; 기초 조명 부하: 공간 유형별; 사람 수: 0; 열 부하 값: 공간 유형별; 전력 부하 단위: 전력 밀도; 조명 부하 단위: 전력 밀도; 1인당 잠열 취득: 58.6142 W; 1인당 현열 취득: 73.2678 W; 개인별 면적: 28.5714 m2; 실제 전력 부하: 0 W; 실제 조명 부하: 0 W; 지정된 구역별 전력 부하: 13.9931; 지정된 구역별 조명 부하: 10.7639; 지정된 전력 부하: 0 W; 지정된 조명 부하: 0 W; 천장속 조명 방사: 20; 총 개인별 열 취득: 131.882 W
치수 - 계산 높이: 1000 mm; 둘레: 8799.98 mm; 면적: 4.79986 m2; 무한한 높이: 5350 mm; 체적: 25.6799 m3

# IfcSpace: 샤프트 29:5255966, 29
In: 지상 2층
LongName: 샤프트; InteriorOrExteriorSpace: INTERNAL
Pset_SpaceCommon - Reference: 샤프트 29; FloorCovering: -; WallCovering: -; CeilingCovering: -
BaseQuantities - NetFloorArea: 6.75001 m2; Height: 4500 mm; GrossPerimeter: 14000 mm; GrossFloorArea: 6.75001 m2; GrossVolume: 30.3751 m3
ID 데이터 - 바닥 마감: -; 번호: 29; 베이스 마감: -; 벽 마감: -; 이름: 샤프트; 천장 마감: -
공정 - 공정: 새 구성
구속조건 - 베이스 간격띄우기: 0 mm; 상한값: 지상 2층; 레벨: 지상 2층; 한계 간격띄우기: 4500 mm
기타 - 거실여부: no; 공정 ID: 0; 카테고리: 룸; 공간분류코드: 33416; 실ID: 216
에너지 해석 - 구역별 실제 전력 부하: 0; 구역별 실제 조명 부하: 0; 기초 전력 부하: 공간 유형별; 기초 조명 부하: 공간 유형별; 사람 수: 0; 열 부하 값: 공간 유형별; 전력 부하 단위: 전력 밀도; 조명 부하 단위: 전력 밀도; 1인당 잠열 취득: 58.6142 W; 1인당 현열 취득: 73.2678 W; 개인별 면적: 28.5714 m2; 실제 전력 부하: 0 W; 실제 조명 부하: 0 W; 지정된 구역별 전력 부하: 13.9931; 지정된 구역별 조명 부하: 10.7639; 지정된 전력 부하: 0 W; 지정된 조명 부하: 0 W; 천장속 조명 방사: 20; 총 개인별 열 취득: 131.882 W
치수 - 계산 높이: 1000 mm; 둘레: 14000 mm; 면적: 6.75001 m2; 무한한 높이: 4500 mm; 체적: 30.3751 m3

# IfcSpace: 샤프트 30:5255969, 30
In: 지상 2층
LongName: 샤프트; InteriorOrExteriorSpace: INTERNAL
Pset_SpaceCommon - Reference: 샤프트 30; FloorCovering: -; WallCovering: -; CeilingCovering: -
BaseQuantities - NetFloorArea: 2.08 m2; Height: 4500 mm; GrossPerimeter: 6800 mm; GrossFloorArea: 2.08 m2; GrossVolume: 9.36 m3
ID 데이터 - 바닥 마감: -; 번호: 30; 베이스 마감: -; 벽 마감: -; 이름: 샤프트; 천장 마감: -
공정 - 공정: 새 구성
구속조건 - 베이스 간격띄우기: 0 mm; 상한값: 지상 2층; 레벨: 지상 2층; 한계 간격띄우기: 4500 mm
기타 - 거실여부: no; 공정 ID: 0; 카테고리: 룸; 공간분류코드: 33416; 실ID: 217
에너지 해석 - 구역별 실제 전력 부하: 0; 구역별 실제 조명 부하: 0; 기초 전력 부하: 공간 유형별; 기초 조명 부하: 공간 유형별; 사람 수: 0; 열 부하 값: 공간 유형별; 전력 부하 단위: 전력 밀도; 조명 부하 단위: 전력 밀도; 1인당 잠열 취득: 58.6142 W; 1인당 현열 취득: 73.2678 W; 개인별 면적: 28.5714 m2; 실제 전력 부하: 0 W; 실제 조명 부하: 0 W; 지정된 구역별 전력 부하: 13.9931; 지정된 구역별 조명 부하: 10.7639; 지정된 전력 부하: 0 W; 지정된 조명 부하: 0 W; 천장속 조명 방사: 20; 총 개인별 열 취득: 131.882 W
치수 - 계산 높이: 1000 mm; 둘레: 6800 mm; 면적: 2.08 m2; 무한한 높이: 4500 mm; 체적: 9.36 m3

# IfcSpace: 샤프트 31:5255972, 31
In: 지상 2층
LongName: 샤프트; InteriorOrExteriorSpace: INTERNAL
Pset_SpaceCommon - Reference: 샤프트 31; FloorCovering: -; WallCovering: -; CeilingCovering: -
BaseQuantities - NetFloorArea: 4.79949 m2; Height: 4500 mm; GrossPerimeter: 8799.96 mm; GrossFloorArea: 4.79949 m2; GrossVolume: 21.5977 m3
ID 데이터 - 바닥 마감: -; 번호: 31; 베이스 마감: -; 벽 마감: -; 이름: 샤프트; 천장 마감: -
공정 - 공정: 새 구성
구속조건 - 베이스 간격띄우기: 0 mm; 상한값: 지상 2층; 레벨: 지상 2층; 한계 간격띄우기: 4500 mm
기타 - 거실여부: no; 공정 ID: 0; 카테고리: 룸; 공간분류코드: 33416; 실ID: 218
에너지 해석 - 구역별 실제 전력 부하: 0; 구역별 실제 조명 부하: 0; 기초 전력 부하: 공간 유형별; 기초 조명 부하: 공간 유형별; 사람 수: 0; 열 부하 값: 공간 유형별; 전력 부하 단위: 전력 밀도; 조명 부하 단위: 전력 밀도; 1인당 잠열 취득: 58.6142 W; 1인당 현열 취득: 73.2678 W; 개인별 면적: 28.5714 m2; 실제 전력 부하: 0 W; 실제 조명 부하: 0 W; 지정된 구역별 전력 부하: 13.9931; 지정된 구역별 조명 부하: 10.7639; 지정된 전력 부하: 0 W; 지정된 조명 부하: 0 W; 천장속 조명 방사: 20; 총 개인별 열 취득: 131.882 W
치수 - 계산 높이: 1000 mm; 둘레: 8799.98 mm; 면적: 4.79949 m2; 무한한 높이: 4500 mm; 체적: 21.5999 m3

# IfcSpace: 샤프트 33:5256032, 33
In: 지상 3층
LongName: 샤프트; InteriorOrExteriorSpace: INTERNAL
Pset_SpaceCommon - Reference: 샤프트 33; FloorCovering: -; WallCovering: -; CeilingCovering: -
BaseQuantities - NetFloorArea: 6.75001 m2; Height: 4100 mm; GrossPerimeter: 14000 mm; GrossFloorArea: 6.75001 m2; GrossVolume: 27.6751 m3
ID 데이터 - 바닥 마감: -; 번호: 33; 베이스 마감: -; 벽 마감: -; 이름: 샤프트; 천장 마감: -
공정 - 공정: 새 구성
구속조건 - 베이스 간격띄우기: 0 mm; 상한값: 지상 3층; 레벨: 지상 3층; 한계 간격띄우기: 4100 mm
기타 - 거실여부: no; 공정 ID: 0; 카테고리: 룸; 공간분류코드: 33416; 실ID: 314
에너지 해석 - 구역별 실제 전력 부하: 0; 구역별 실제 조명 부하: 0; 기초 전력 부하: 공간 유형별; 기초 조명 부하: 공간 유형별; 사람 수: 0; 열 부하 값: 공간 유형별; 전력 부하 단위: 전력 밀도; 조명 부하 단위: 전력 밀도; 1인당 잠열 취득: 58.6142 W; 1인당 현열 취득: 73.2678 W; 개인별 면적: 28.5714 m2; 실제 전력 부하: 0 W; 실제 조명 부하: 0 W; 지정된 구역별 전력 부하: 13.9931; 지정된 구역별 조명 부하: 10.7639; 지정된 전력 부하: 0 W; 지정된 조명 부하: 0 W; 천장속 조명 방사: 20; 총 개인별 열 취득: 131.882 W
치수 - 계산 높이: 1000 mm; 둘레: 14000 mm; 면적: 6.75001 m2; 무한한 높이: 4100 mm; 체적: 27.6751 m3

# IfcSpace: 샤프트 34:5256035, 34
In: 지상 3층
LongName: 샤프트; InteriorOrExteriorSpace: INTERNAL
Pset_SpaceCommon - Reference: 샤프트 34; FloorCovering: -; WallCovering: -; CeilingCovering: -
BaseQuantities - NetFloorArea: 2.08 m2; Height: 4100 mm; GrossPerimeter: 6800 mm; GrossFloorArea: 2.08 m2; GrossVolume: 8.528 m3
ID 데이터 - 바닥 마감: -; 번호: 34; 베이스 마감: -; 벽 마감: -; 이름: 샤프트; 천장 마감: -
공정 - 공정: 새 구성
구속조건 - 베이스 간격띄우기: 0 mm; 상한값: 지상 3층; 레벨: 지상 3층; 한계 간격띄우기: 4100 mm
기타 - 거실여부: no; 공정 ID: 0; 카테고리: 룸; 공간분류코드: 33416; 실ID: 315
에너지 해석 - 구역별 실제 전력 부하: 0; 구역별 실제 조명 부하: 0; 기초 전력 부하: 공간 유형별; 기초 조명 부하: 공간 유형별; 사람 수: 0; 열 부하 값: 공간 유형별; 전력 부하 단위: 전력 밀도; 조명 부하 단위: 전력 밀도; 1인당 잠열 취득: 58.6142 W; 1인당 현열 취득: 73.2678 W; 개인별 면적: 28.5714 m2; 실제 전력 부하: 0 W; 실제 조명 부하: 0 W; 지정된 구역별 전력 부하: 13.9931; 지정된 구역별 조명 부하: 10.7639; 지정된 전력 부하: 0 W; 지정된 조명 부하: 0 W; 천장속 조명 방사: 20; 총 개인별 열 취득: 131.882 W
치수 - 계산 높이: 1000 mm; 둘레: 6800 mm; 면적: 2.08 m2; 무한한 높이: 4100 mm; 체적: 8.528 m3

# IfcSpace: 샤프트 35:5256038, 35
In: 지상 3층
LongName: 샤프트; InteriorOrExteriorSpace: INTERNAL
Pset_SpaceCommon - Reference: 샤프트 35; FloorCovering: -; WallCovering: -; CeilingCovering: -
BaseQuantities - NetFloorArea: 4.79985 m2; Height: 4100 mm; GrossPerimeter: 8799.97 mm; GrossFloorArea: 4.79985 m2; GrossVolume: 19.6794 m3
ID 데이터 - 바닥 마감: -; 번호: 35; 베이스 마감: -; 벽 마감: -; 이름: 샤프트; 천장 마감: -
공정 - 공정: 새 구성
구속조건 - 베이스 간격띄우기: 0 mm; 상한값: 지상 3층; 레벨: 지상 3층; 한계 간격띄우기: 4100 mm
기타 - 거실여부: no; 공정 ID: 0; 카테고리: 룸; 공간분류코드: 33416; 실ID: 316
에너지 해석 - 구역별 실제 전력 부하: 0; 구역별 실제 조명 부하: 0; 기초 전력 부하: 공간 유형별; 기초 조명 부하: 공간 유형별; 사람 수: 0; 열 부하 값: 공간 유형별; 전력 부하 단위: 전력 밀도; 조명 부하 단위: 전력 밀도; 1인당 잠열 취득: 58.6142 W; 1인당 현열 취득: 73.2678 W; 개인별 면적: 28.5714 m2; 실제 전력 부하: 0 W; 실제 조명 부하: 0 W; 지정된 구역별 전력 부하: 13.9931; 지정된 구역별 조명 부하: 10.7639; 지정된 전력 부하: 0 W; 지정된 조명 부하: 0 W; 천장속 조명 방사: 20; 총 개인별 열 취득: 131.882 W
치수 - 계산 높이: 1000 mm; 둘레: 8799.98 mm; 면적: 4.79985 m2; 무한한 높이: 4100 mm; 체적: 19.6799 m3

# IfcSpace: 샤프트 42:5256076, 42
In: 지상 4층
LongName: 샤프트; InteriorOrExteriorSpace: INTERNAL
Pset_SpaceCommon - Reference: 샤프트 42; FloorCovering: -; WallCovering: -; CeilingCovering: -
BaseQuantities - NetFloorArea: 6.75005 m2; Height: 4100 mm; GrossPerimeter: 14000 mm; GrossFloorArea: 6.75005 m2; GrossVolume: 27.6752 m3
ID 데이터 - 바닥 마감: -; 번호: 42; 베이스 마감: -; 벽 마감: -; 이름: 샤프트; 천장 마감: -
공정 - 공정: 새 구성
구속조건 - 베이스 간격띄우기: 0 mm; 상한값: 지상 4층; 레벨: 지상 4층; 한계 간격띄우기: 4100 mm
기타 - 거실여부: no; 공정 ID: 0; 카테고리: 룸; 공간분류코드: 33416; 실ID: 416
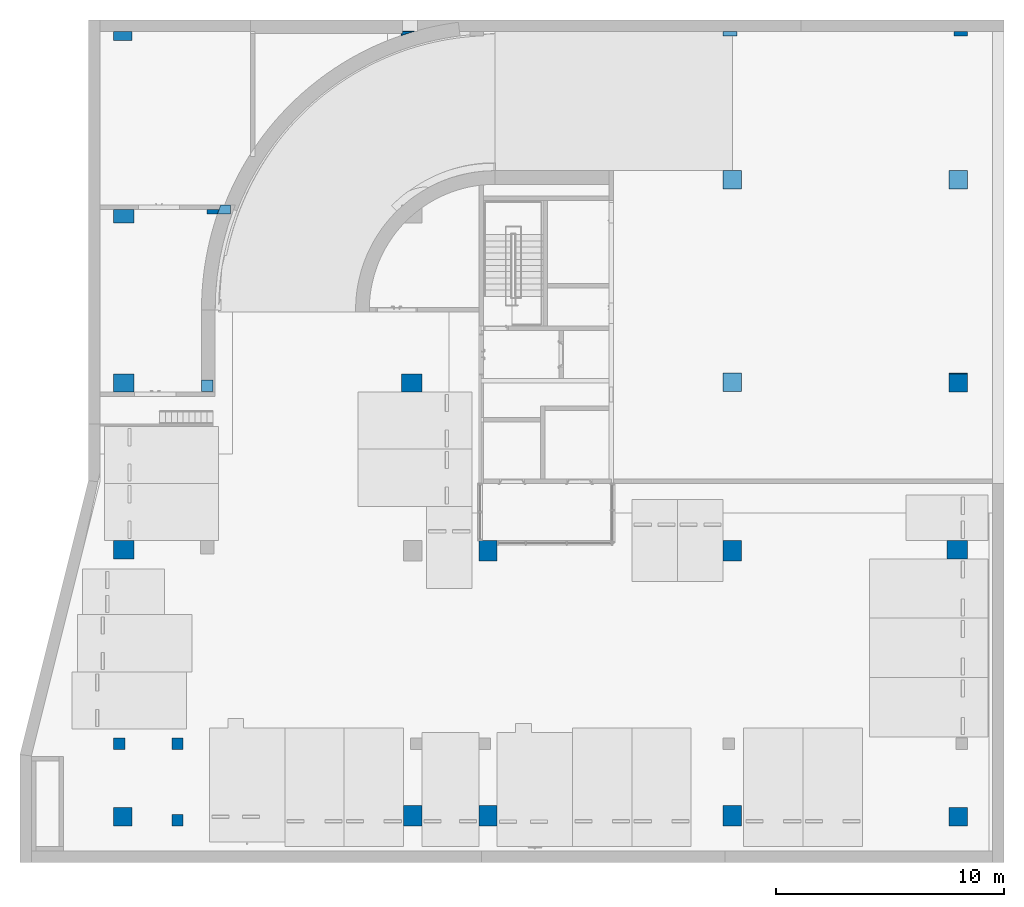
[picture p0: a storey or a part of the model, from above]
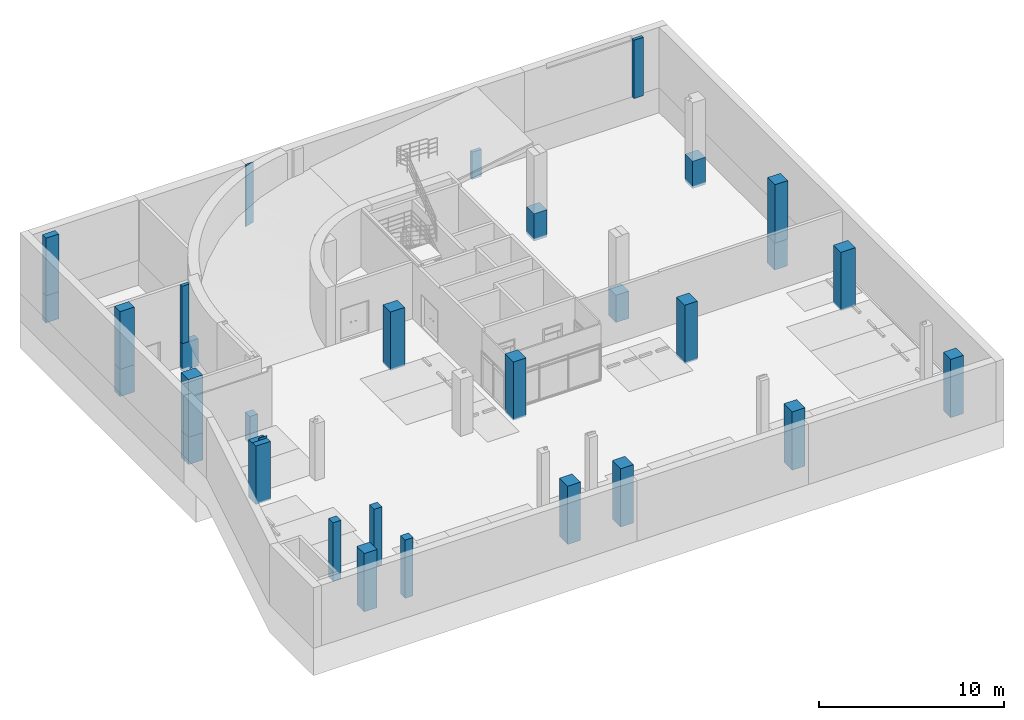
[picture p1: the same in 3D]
Properties of the parts of a building model (IFC2X3), part 4 of 39

# IfcSpace: 샤프트 42:5256076, 42
에너지 해석 - 구역별 실제 전력 부하: 0; 구역별 실제 조명 부하: 0; 기초 전력 부하: 공간 유형별; 기초 조명 부하: 공간 유형별; 사람 수: 0; 열 부하 값: 공간 유형별; 전력 부하 단위: 전력 밀도; 조명 부하 단위: 전력 밀도; 1인당 잠열 취득: 58.6142 W; 1인당 현열 취득: 73.2678 W; 개인별 면적: 28.5714 m2; 실제 전력 부하: 0 W; 실제 조명 부하: 0 W; 지정된 구역별 전력 부하: 13.9931; 지정된 구역별 조명 부하: 10.7639; 지정된 전력 부하: 0 W; 지정된 조명 부하: 0 W; 천장속 조명 방사: 20; 총 개인별 열 취득: 131.882 W
치수 - 계산 높이: 1000 mm; 둘레: 14000 mm; 면적: 6.75005 m2; 무한한 높이: 4100 mm; 체적: 27.6752 m3

# IfcSpace: 샤프트 43:5256079, 43
In: 지상 4층
LongName: 샤프트; InteriorOrExteriorSpace: INTERNAL
Pset_SpaceCommon - Reference: 샤프트 43; FloorCovering: -; WallCovering: -; CeilingCovering: -
BaseQuantities - NetFloorArea: 2.08 m2; Height: 4100 mm; GrossPerimeter: 6800 mm; GrossFloorArea: 2.08 m2; GrossVolume: 8.528 m3
ID 데이터 - 바닥 마감: -; 번호: 43; 베이스 마감: -; 벽 마감: -; 이름: 샤프트; 천장 마감: -
공정 - 공정: 새 구성
구속조건 - 베이스 간격띄우기: 0 mm; 상한값: 지상 4층; 레벨: 지상 4층; 한계 간격띄우기: 4100 mm
기타 - 거실여부: no; 공정 ID: 0; 카테고리: 룸; 공간분류코드: 33416; 실ID: 417
에너지 해석 - 구역별 실제 전력 부하: 0; 구역별 실제 조명 부하: 0; 기초 전력 부하: 공간 유형별; 기초 조명 부하: 공간 유형별; 사람 수: 0; 열 부하 값: 공간 유형별; 전력 부하 단위: 전력 밀도; 조명 부하 단위: 전력 밀도; 1인당 잠열 취득: 58.6142 W; 1인당 현열 취득: 73.2678 W; 개인별 면적: 28.5714 m2; 실제 전력 부하: 0 W; 실제 조명 부하: 0 W; 지정된 구역별 전력 부하: 13.9931; 지정된 구역별 조명 부하: 10.7639; 지정된 전력 부하: 0 W; 지정된 조명 부하: 0 W; 천장속 조명 방사: 20; 총 개인별 열 취득: 131.882 W
치수 - 계산 높이: 1000 mm; 둘레: 6800 mm; 면적: 2.08 m2; 무한한 높이: 4100 mm; 체적: 8.528 m3

# IfcSpace: 샤프트 44:5256082, 44
In: 지상 4층
LongName: 샤프트; InteriorOrExteriorSpace: INTERNAL
Pset_SpaceCommon - Reference: 샤프트 44; FloorCovering: -; WallCovering: -; CeilingCovering: -
BaseQuantities - NetFloorArea: 4.80198 m2; Height: 4100 mm; GrossFloorArea: 4.80198 m2; GrossVolume: 19.6881 m3
ID 데이터 - 바닥 마감: -; 번호: 44; 베이스 마감: -; 벽 마감: -; 이름: 샤프트; 천장 마감: -
공정 - 공정: 새 구성
구속조건 - 베이스 간격띄우기: 0 mm; 상한값: 지상 4층; 레벨: 지상 4층; 한계 간격띄우기: 4100 mm
기타 - 거실여부: no; 공정 ID: 0; 카테고리: 룸; 공간분류코드: 33416; 실ID: 418
에너지 해석 - 구역별 실제 전력 부하: 0; 구역별 실제 조명 부하: 0; 기초 전력 부하: 공간 유형별; 기초 조명 부하: 공간 유형별; 사람 수: 0; 열 부하 값: 공간 유형별; 전력 부하 단위: 전력 밀도; 조명 부하 단위: 전력 밀도; 1인당 잠열 취득: 58.6142 W; 1인당 현열 취득: 73.2678 W; 개인별 면적: 28.5714 m2; 실제 전력 부하: 0 W; 실제 조명 부하: 0 W; 지정된 구역별 전력 부하: 13.9931; 지정된 구역별 조명 부하: 10.7639; 지정된 전력 부하: 0 W; 지정된 조명 부하: 0 W; 천장속 조명 방사: 20; 총 개인별 열 취득: 131.882 W
치수 - 계산 높이: 1000 mm; 둘레: 9199.98 mm; 면적: 4.80198 m2; 무한한 높이: 4100 mm; 체적: 19.6878 m3

# IfcSpace: 샤프트 46:5256104, 46
In: 지상 5층
LongName: 샤프트; InteriorOrExteriorSpace: INTERNAL
Pset_SpaceCommon - Reference: 샤프트 46; FloorCovering: -; WallCovering: -; CeilingCovering: -
BaseQuantities - NetFloorArea: 6.75001 m2; Height: 4100 mm; GrossPerimeter: 14000 mm; GrossFloorArea: 6.75001 m2; GrossVolume: 27.6751 m3
ID 데이터 - 바닥 마감: -; 번호: 46; 베이스 마감: -; 벽 마감: -; 이름: 샤프트; 천장 마감: -
공정 - 공정: 새 구성
구속조건 - 베이스 간격띄우기: 0 mm; 상한값: 지상 5층; 레벨: 지상 5층; 한계 간격띄우기: 4100 mm
기타 - 거실여부: no; 공정 ID: 0; 카테고리: 룸; 공간분류코드: 33416; 실ID: 514
에너지 해석 - 구역별 실제 전력 부하: 0; 구역별 실제 조명 부하: 0; 기초 전력 부하: 공간 유형별; 기초 조명 부하: 공간 유형별; 사람 수: 0; 열 부하 값: 공간 유형별; 전력 부하 단위: 전력 밀도; 조명 부하 단위: 전력 밀도; 1인당 잠열 취득: 58.6142 W; 1인당 현열 취득: 73.2678 W; 개인별 면적: 28.5714 m2; 실제 전력 부하: 0 W; 실제 조명 부하: 0 W; 지정된 구역별 전력 부하: 13.9931; 지정된 구역별 조명 부하: 10.7639; 지정된 전력 부하: 0 W; 지정된 조명 부하: 0 W; 천장속 조명 방사: 20; 총 개인별 열 취득: 131.882 W
치수 - 계산 높이: 1000 mm; 둘레: 14000 mm; 면적: 6.75001 m2; 무한한 높이: 4100 mm; 체적: 27.6751 m3

# IfcSpace: 샤프트 47:5256107, 47
In: 지상 5층
LongName: 샤프트; InteriorOrExteriorSpace: INTERNAL
Pset_SpaceCommon - Reference: 샤프트 47; FloorCovering: -; WallCovering: -; CeilingCovering: -
BaseQuantities - NetFloorArea: 2.08 m2; Height: 4100 mm; GrossPerimeter: 6800 mm; GrossFloorArea: 2.08 m2; GrossVolume: 8.528 m3
ID 데이터 - 바닥 마감: -; 번호: 47; 베이스 마감: -; 벽 마감: -; 이름: 샤프트; 천장 마감: -
공정 - 공정: 새 구성
구속조건 - 베이스 간격띄우기: 0 mm; 상한값: 지상 5층; 레벨: 지상 5층; 한계 간격띄우기: 4100 mm
기타 - 거실여부: no; 공정 ID: 0; 카테고리: 룸; 공간분류코드: 33416; 실ID: 515
에너지 해석 - 구역별 실제 전력 부하: 0; 구역별 실제 조명 부하: 0; 기초 전력 부하: 공간 유형별; 기초 조명 부하: 공간 유형별; 사람 수: 0; 열 부하 값: 공간 유형별; 전력 부하 단위: 전력 밀도; 조명 부하 단위: 전력 밀도; 1인당 잠열 취득: 58.6142 W; 1인당 현열 취득: 73.2678 W; 개인별 면적: 28.5714 m2; 실제 전력 부하: 0 W; 실제 조명 부하: 0 W; 지정된 구역별 전력 부하: 13.9931; 지정된 구역별 조명 부하: 10.7639; 지정된 전력 부하: 0 W; 지정된 조명 부하: 0 W; 천장속 조명 방사: 20; 총 개인별 열 취득: 131.882 W
치수 - 계산 높이: 1000 mm; 둘레: 6800 mm; 면적: 2.08 m2; 무한한 높이: 4100 mm; 체적: 8.528 m3

# IfcSpace: 샤프트 48:5256110, 48
In: 지상 5층
LongName: 샤프트; InteriorOrExteriorSpace: INTERNAL
Pset_SpaceCommon - Reference: 샤프트 48; FloorCovering: -; WallCovering: -; CeilingCovering: -
BaseQuantities - NetFloorArea: 4.79985 m2; Height: 4100 mm; GrossPerimeter: 8799.97 mm; GrossFloorArea: 4.79985 m2; GrossVolume: 19.6794 m3
ID 데이터 - 바닥 마감: -; 번호: 48; 베이스 마감: -; 벽 마감: -; 이름: 샤프트; 천장 마감: -
공정 - 공정: 새 구성
구속조건 - 베이스 간격띄우기: 0 mm; 상한값: 지상 5층; 레벨: 지상 5층; 한계 간격띄우기: 4100 mm
기타 - 거실여부: no; 공정 ID: 0; 카테고리: 룸; 공간분류코드: 33416; 실ID: 516
에너지 해석 - 구역별 실제 전력 부하: 0; 구역별 실제 조명 부하: 0; 기초 전력 부하: 공간 유형별; 기초 조명 부하: 공간 유형별; 사람 수: 0; 열 부하 값: 공간 유형별; 전력 부하 단위: 전력 밀도; 조명 부하 단위: 전력 밀도; 1인당 잠열 취득: 58.6142 W; 1인당 현열 취득: 73.2678 W; 개인별 면적: 28.5714 m2; 실제 전력 부하: 0 W; 실제 조명 부하: 0 W; 지정된 구역별 전력 부하: 13.9931; 지정된 구역별 조명 부하: 10.7639; 지정된 전력 부하: 0 W; 지정된 조명 부하: 0 W; 천장속 조명 방사: 20; 총 개인별 열 취득: 131.882 W
치수 - 계산 높이: 1000 mm; 둘레: 8799.98 mm; 면적: 4.79985 m2; 무한한 높이: 4100 mm; 체적: 19.6799 m3

# IfcSpace: 샤프트 55:5256154, 55
In: 지상 6층
LongName: 샤프트; InteriorOrExteriorSpace: INTERNAL
Pset_SpaceCommon - Reference: 샤프트 55; FloorCovering: -; WallCovering: -; CeilingCovering: -
BaseQuantities - NetFloorArea: 6.7308 m2; Height: 4100 mm; GrossPerimeter: 14192.2 mm; GrossFloorArea: 6.7308 m2; GrossVolume: 27.5963 m3
ID 데이터 - 바닥 마감: -; 번호: 55; 베이스 마감: -; 벽 마감: -; 이름: 샤프트; 천장 마감: -
공정 - 공정: 새 구성
구속조건 - 베이스 간격띄우기: 0 mm; 상한값: 지상 6층; 레벨: 지상 6층; 한계 간격띄우기: 4100 mm
기타 - 거실여부: no; 공정 ID: 0; 카테고리: 룸; 공간분류코드: 33416; 실ID: 617
에너지 해석 - 구역별 실제 전력 부하: 0; 구역별 실제 조명 부하: 0; 기초 전력 부하: 공간 유형별; 기초 조명 부하: 공간 유형별; 사람 수: 0; 열 부하 값: 공간 유형별; 전력 부하 단위: 전력 밀도; 조명 부하 단위: 전력 밀도; 1인당 잠열 취득: 58.6142 W; 1인당 현열 취득: 73.2678 W; 개인별 면적: 28.5714 m2; 실제 전력 부하: 0 W; 실제 조명 부하: 0 W; 지정된 구역별 전력 부하: 13.9931; 지정된 구역별 조명 부하: 10.7639; 지정된 전력 부하: 0 W; 지정된 조명 부하: 0 W; 천장속 조명 방사: 20; 총 개인별 열 취득: 131.882 W
치수 - 계산 높이: 1000 mm; 둘레: 14192.2 mm; 면적: 6.7308 m2; 무한한 높이: 4100 mm; 체적: 27.5963 m3

# IfcSpace: 샤프트 56:5256157, 56
In: 지상 6층
LongName: 샤프트; InteriorOrExteriorSpace: INTERNAL
Pset_SpaceCommon - Reference: 샤프트 56; FloorCovering: -; WallCovering: -; CeilingCovering: -
BaseQuantities - NetFloorArea: 2.08 m2; Height: 4100 mm; GrossPerimeter: 6800 mm; GrossFloorArea: 2.08 m2; GrossVolume: 8.528 m3
ID 데이터 - 바닥 마감: -; 번호: 56; 베이스 마감: -; 벽 마감: -; 이름: 샤프트; 천장 마감: -
공정 - 공정: 새 구성
구속조건 - 베이스 간격띄우기: 0 mm; 상한값: 지상 6층; 레벨: 지상 6층; 한계 간격띄우기: 4100 mm
기타 - 거실여부: no; 공정 ID: 0; 카테고리: 룸; 공간분류코드: 33416; 실ID: 618
에너지 해석 - 구역별 실제 전력 부하: 0; 구역별 실제 조명 부하: 0; 기초 전력 부하: 공간 유형별; 기초 조명 부하: 공간 유형별; 사람 수: 0; 열 부하 값: 공간 유형별; 전력 부하 단위: 전력 밀도; 조명 부하 단위: 전력 밀도; 1인당 잠열 취득: 58.6142 W; 1인당 현열 취득: 73.2678 W; 개인별 면적: 28.5714 m2; 실제 전력 부하: 0 W; 실제 조명 부하: 0 W; 지정된 구역별 전력 부하: 13.9931; 지정된 구역별 조명 부하: 10.7639; 지정된 전력 부하: 0 W; 지정된 조명 부하: 0 W; 천장속 조명 방사: 20; 총 개인별 열 취득: 131.882 W
치수 - 계산 높이: 1000 mm; 둘레: 6800 mm; 면적: 2.08 m2; 무한한 높이: 4100 mm; 체적: 8.528 m3

# IfcSpace: 샤프트 57:5256160, 57
In: 지상 6층
LongName: 샤프트; InteriorOrExteriorSpace: INTERNAL
Pset_SpaceCommon - Reference: 샤프트 57; FloorCovering: -; WallCovering: -; CeilingCovering: -
BaseQuantities - NetFloorArea: 4.79985 m2; Height: 4100 mm; GrossPerimeter: 8799.97 mm; GrossFloorArea: 4.79985 m2; GrossVolume: 19.6794 m3
ID 데이터 - 바닥 마감: -; 번호: 57; 베이스 마감: -; 벽 마감: -; 이름: 샤프트; 천장 마감: -
공정 - 공정: 새 구성
구속조건 - 베이스 간격띄우기: 0 mm; 상한값: 지상 6층; 레벨: 지상 6층; 한계 간격띄우기: 4100 mm
기타 - 거실여부: no; 공정 ID: 0; 카테고리: 룸; 공간분류코드: 33416; 실ID: 619
에너지 해석 - 구역별 실제 전력 부하: 0; 구역별 실제 조명 부하: 0; 기초 전력 부하: 공간 유형별; 기초 조명 부하: 공간 유형별; 사람 수: 0; 열 부하 값: 공간 유형별; 전력 부하 단위: 전력 밀도; 조명 부하 단위: 전력 밀도; 1인당 잠열 취득: 58.6142 W; 1인당 현열 취득: 73.2678 W; 개인별 면적: 28.5714 m2; 실제 전력 부하: 0 W; 실제 조명 부하: 0 W; 지정된 구역별 전력 부하: 13.9931; 지정된 구역별 조명 부하: 10.7639; 지정된 전력 부하: 0 W; 지정된 조명 부하: 0 W; 천장속 조명 방사: 20; 총 개인별 열 취득: 131.882 W
치수 - 계산 높이: 1000 mm; 둘레: 8799.98 mm; 면적: 4.79985 m2; 무한한 높이: 4100 mm; 체적: 19.6799 m3

# IfcSpace: 샤프트 58:5256170, 58
In: 지상 7층
LongName: 샤프트; InteriorOrExteriorSpace: INTERNAL
Pset_SpaceCommon - Reference: 샤프트 58; FloorCovering: -; WallCovering: -; CeilingCovering: -
BaseQuantities - NetFloorArea: 6.75001 m2; Height: 4100 mm; GrossPerimeter: 14000 mm; GrossFloorArea: 6.75001 m2; GrossVolume: 27.6751 m3
ID 데이터 - 바닥 마감: -; 번호: 58; 베이스 마감: -; 벽 마감: -; 이름: 샤프트; 천장 마감: -
공정 - 공정: 새 구성
구속조건 - 베이스 간격띄우기: 0 mm; 상한값: 지상 7층; 레벨: 지상 7층; 한계 간격띄우기: 4100 mm
기타 - 거실여부: no; 공정 ID: 0; 카테고리: 룸; 공간분류코드: 33416; 실ID: 714
에너지 해석 - 구역별 실제 전력 부하: 0; 구역별 실제 조명 부하: 0; 기초 전력 부하: 공간 유형별; 기초 조명 부하: 공간 유형별; 사람 수: 0; 열 부하 값: 공간 유형별; 전력 부하 단위: 전력 밀도; 조명 부하 단위: 전력 밀도; 1인당 잠열 취득: 58.6142 W; 1인당 현열 취득: 73.2678 W; 개인별 면적: 28.5714 m2; 실제 전력 부하: 0 W; 실제 조명 부하: 0 W; 지정된 구역별 전력 부하: 13.9931; 지정된 구역별 조명 부하: 10.7639; 지정된 전력 부하: 0 W; 지정된 조명 부하: 0 W; 천장속 조명 방사: 20; 총 개인별 열 취득: 131.882 W
치수 - 계산 높이: 1000 mm; 둘레: 14000 mm; 면적: 6.75001 m2; 무한한 높이: 4100 mm; 체적: 27.6751 m3

# IfcSpace: 샤프트 59:5256173, 59
In: 지상 7층
LongName: 샤프트; InteriorOrExteriorSpace: INTERNAL
Pset_SpaceCommon - Reference: 샤프트 59; FloorCovering: -; WallCovering: -; CeilingCovering: -
BaseQuantities - NetFloorArea: 2.08 m2; Height: 4100 mm; GrossPerimeter: 6800 mm; GrossFloorArea: 2.08 m2; GrossVolume: 8.528 m3
ID 데이터 - 바닥 마감: -; 번호: 59; 베이스 마감: -; 벽 마감: -; 이름: 샤프트; 천장 마감: -
공정 - 공정: 새 구성
구속조건 - 베이스 간격띄우기: 0 mm; 상한값: 지상 7층; 레벨: 지상 7층; 한계 간격띄우기: 4100 mm
기타 - 거실여부: no; 공정 ID: 0; 카테고리: 룸; 공간분류코드: 33416; 실ID: 715
에너지 해석 - 구역별 실제 전력 부하: 0; 구역별 실제 조명 부하: 0; 기초 전력 부하: 공간 유형별; 기초 조명 부하: 공간 유형별; 사람 수: 0; 열 부하 값: 공간 유형별; 전력 부하 단위: 전력 밀도; 조명 부하 단위: 전력 밀도; 1인당 잠열 취득: 58.6142 W; 1인당 현열 취득: 73.2678 W; 개인별 면적: 28.5714 m2; 실제 전력 부하: 0 W; 실제 조명 부하: 0 W; 지정된 구역별 전력 부하: 13.9931; 지정된 구역별 조명 부하: 10.7639; 지정된 전력 부하: 0 W; 지정된 조명 부하: 0 W; 천장속 조명 방사: 20; 총 개인별 열 취득: 131.882 W
치수 - 계산 높이: 1000 mm; 둘레: 6800 mm; 면적: 2.08 m2; 무한한 높이: 4100 mm; 체적: 8.528 m3

# IfcSpace: 샤프트 60:5256176, 60
In: 지상 7층
LongName: 샤프트; InteriorOrExteriorSpace: INTERNAL
Pset_SpaceCommon - Reference: 샤프트 60; FloorCovering: -; WallCovering: -; CeilingCovering: -
BaseQuantities - NetFloorArea: 4.79985 m2; Height: 4100 mm; GrossPerimeter: 8799.97 mm; GrossFloorArea: 4.79985 m2; GrossVolume: 19.6794 m3
ID 데이터 - 바닥 마감: -; 번호: 60; 벽 마감: -; 이름: 샤프트; 천장 마감: -
공정 - 공정: 새 구성
구속조건 - 베이스 간격띄우기: 0 mm; 상한값: 지상 7층; 레벨: 지상 7층; 한계 간격띄우기: 4100 mm
기타 - 거실여부: no; 공정 ID: 0; 카테고리: 룸; 공간분류코드: 33416; 실ID: 716
에너지 해석 - 구역별 실제 전력 부하: 0; 구역별 실제 조명 부하: 0; 기초 전력 부하: 공간 유형별; 기초 조명 부하: 공간 유형별; 사람 수: 0; 열 부하 값: 공간 유형별; 전력 부하 단위: 전력 밀도; 조명 부하 단위: 전력 밀도; 1인당 잠열 취득: 58.6142 W; 1인당 현열 취득: 73.2678 W; 개인별 면적: 28.5714 m2; 실제 전력 부하: 0 W; 실제 조명 부하: 0 W; 지정된 구역별 전력 부하: 13.9931; 지정된 구역별 조명 부하: 10.7639; 지정된 전력 부하: 0 W; 지정된 조명 부하: 0 W; 천장속 조명 방사: 20; 총 개인별 열 취득: 131.882 W
치수 - 계산 높이: 1000 mm; 둘레: 8799.98 mm; 면적: 4.79985 m2; 무한한 높이: 4100 mm; 체적: 19.6799 m3

# IfcSpace: 샤프트 67:5256215, 67
In: 지상 8층
LongName: 샤프트; InteriorOrExteriorSpace: INTERNAL
Pset_SpaceCommon - Reference: 샤프트 67; FloorCovering: -; WallCovering: -; CeilingCovering: -
BaseQuantities - NetFloorArea: 6.75001 m2; Height: 4100 mm; GrossPerimeter: 14000 mm; GrossFloorArea: 6.75001 m2; GrossVolume: 27.6751 m3
ID 데이터 - 바닥 마감: -; 번호: 67; 베이스 마감: -; 벽 마감: -; 이름: 샤프트; 천장 마감: -
공정 - 공정: 새 구성
구속조건 - 베이스 간격띄우기: 0 mm; 상한값: 지상 8층; 레벨: 지상 8층; 한계 간격띄우기: 4100 mm
기타 - 거실여부: no; 공정 ID: 0; 카테고리: 룸; 공간분류코드: 33416; 실ID: 814
에너지 해석 - 구역별 실제 전력 부하: 0; 구역별 실제 조명 부하: 0; 기초 전력 부하: 공간 유형별; 기초 조명 부하: 공간 유형별; 사람 수: 0; 열 부하 값: 공간 유형별; 전력 부하 단위: 전력 밀도; 조명 부하 단위: 전력 밀도; 1인당 잠열 취득: 58.6142 W; 1인당 현열 취득: 73.2678 W; 개인별 면적: 28.5714 m2; 실제 전력 부하: 0 W; 실제 조명 부하: 0 W; 지정된 구역별 전력 부하: 13.9931; 지정된 구역별 조명 부하: 10.7639; 지정된 전력 부하: 0 W; 지정된 조명 부하: 0 W; 천장속 조명 방사: 20; 총 개인별 열 취득: 131.882 W
치수 - 계산 높이: 1000 mm; 둘레: 14000 mm; 면적: 6.75001 m2; 무한한 높이: 4100 mm; 체적: 27.6751 m3

# IfcSpace: 샤프트 68:5256218, 68
In: 지상 8층
LongName: 샤프트; InteriorOrExteriorSpace: INTERNAL
Pset_SpaceCommon - Reference: 샤프트 68; FloorCovering: -; WallCovering: -; CeilingCovering: -
BaseQuantities - NetFloorArea: 2.08 m2; Height: 4100 mm; GrossPerimeter: 6800 mm; GrossFloorArea: 2.08 m2; GrossVolume: 8.528 m3
ID 데이터 - 바닥 마감: -; 번호: 68; 베이스 마감: -; 벽 마감: -; 이름: 샤프트; 천장 마감: -
공정 - 공정: 새 구성
구속조건 - 베이스 간격띄우기: 0 mm; 상한값: 지상 8층; 레벨: 지상 8층; 한계 간격띄우기: 4100 mm
기타 - 거실여부: no; 공정 ID: 0; 카테고리: 룸; 공간분류코드: 33416; 실ID: 815
에너지 해석 - 구역별 실제 전력 부하: 0; 구역별 실제 조명 부하: 0; 기초 전력 부하: 공간 유형별; 기초 조명 부하: 공간 유형별; 사람 수: 0; 열 부하 값: 공간 유형별; 전력 부하 단위: 전력 밀도; 조명 부하 단위: 전력 밀도; 1인당 잠열 취득: 58.6142 W; 1인당 현열 취득: 73.2678 W; 개인별 면적: 28.5714 m2; 실제 전력 부하: 0 W; 실제 조명 부하: 0 W; 지정된 구역별 전력 부하: 13.9931; 지정된 구역별 조명 부하: 10.7639; 지정된 전력 부하: 0 W; 지정된 조명 부하: 0 W; 천장속 조명 방사: 20; 총 개인별 열 취득: 131.882 W
치수 - 계산 높이: 1000 mm; 둘레: 6800 mm; 면적: 2.08 m2; 무한한 높이: 4100 mm; 체적: 8.528 m3

# IfcSpace: 샤프트 69:5256227, 69
In: 지상 8층
LongName: 샤프트; InteriorOrExteriorSpace: INTERNAL
Pset_SpaceCommon - Reference: 샤프트 69; FloorCovering: -; WallCovering: -; CeilingCovering: -
BaseQuantities - NetFloorArea: 4.79985 m2; Height: 4100 mm; GrossPerimeter: 8799.97 mm; GrossFloorArea: 4.79985 m2; GrossVolume: 19.6794 m3
ID 데이터 - 바닥 마감: -; 번호: 69; 베이스 마감: -; 벽 마감: -; 이름: 샤프트; 천장 마감: -
공정 - 공정: 새 구성
구속조건 - 베이스 간격띄우기: 0 mm; 상한값: 지상 8층; 레벨: 지상 8층; 한계 간격띄우기: 4100 mm
기타 - 거실여부: no; 공정 ID: 0; 카테고리: 룸; 공간분류코드: 33416; 실ID: 816
에너지 해석 - 구역별 실제 전력 부하: 0; 구역별 실제 조명 부하: 0; 기초 전력 부하: 공간 유형별; 기초 조명 부하: 공간 유형별; 사람 수: 0; 열 부하 값: 공간 유형별; 전력 부하 단위: 전력 밀도; 조명 부하 단위: 전력 밀도; 1인당 잠열 취득: 58.6142 W; 1인당 현열 취득: 73.2678 W; 개인별 면적: 28.5714 m2; 실제 전력 부하: 0 W; 실제 조명 부하: 0 W; 지정된 구역별 전력 부하: 13.9931; 지정된 구역별 조명 부하: 10.7639; 지정된 전력 부하: 0 W; 지정된 조명 부하: 0 W; 천장속 조명 방사: 20; 총 개인별 열 취득: 131.882 W
치수 - 계산 높이: 1000 mm; 둘레: 8799.98 mm; 면적: 4.79985 m2; 무한한 높이: 4100 mm; 체적: 19.6799 m3

# IfcSpace: 샤프트 70:5256271, 70
In: 지상 9층
LongName: 샤프트; InteriorOrExteriorSpace: INTERNAL
Pset_SpaceCommon - Reference: 샤프트 70; FloorCovering: -; WallCovering: -; CeilingCovering: -
BaseQuantities - NetFloorArea: 6.75001 m2; Height: 4500 mm; GrossPerimeter: 14000 mm; GrossFloorArea: 6.75001 m2; GrossVolume: 30.3751 m3
ID 데이터 - 바닥 마감: -; 번호: 70; 베이스 마감: -; 벽 마감: -; 이름: 샤프트; 천장 마감: -
공정 - 공정: 새 구성
구속조건 - 베이스 간격띄우기: 0 mm; 상한값: 지상 9층; 레벨: 지상 9층; 한계 간격띄우기: 4500 mm
기타 - 거실여부: no; 공정 ID: 0; 카테고리: 룸; 공간분류코드: 33416; 실ID: 910
에너지 해석 - 구역별 실제 전력 부하: 0; 구역별 실제 조명 부하: 0; 기초 전력 부하: 공간 유형별; 기초 조명 부하: 공간 유형별; 사람 수: 0; 열 부하 값: 공간 유형별; 전력 부하 단위: 전력 밀도; 조명 부하 단위: 전력 밀도; 1인당 잠열 취득: 58.6142 W; 1인당 현열 취득: 73.2678 W; 개인별 면적: 28.5714 m2; 실제 전력 부하: 0 W; 실제 조명 부하: 0 W; 지정된 구역별 전력 부하: 13.9931; 지정된 구역별 조명 부하: 10.7639; 지정된 전력 부하: 0 W; 지정된 조명 부하: 0 W; 천장속 조명 방사: 20; 총 개인별 열 취득: 131.882 W
치수 - 계산 높이: 1000 mm; 둘레: 14000 mm; 면적: 6.75001 m2; 무한한 높이: 4500 mm; 체적: 30.3751 m3

# IfcSpace: 샤프트 71:5256274, 71
In: 지상 9층
LongName: 샤프트; InteriorOrExteriorSpace: INTERNAL
Pset_SpaceCommon - Reference: 샤프트 71; FloorCovering: -; WallCovering: -; CeilingCovering: -
BaseQuantities - NetFloorArea: 2.08 m2; Height: 4500 mm; GrossPerimeter: 6800 mm; GrossFloorArea: 2.08 m2; GrossVolume: 9.36 m3
ID 데이터 - 바닥 마감: -; 번호: 71; 베이스 마감: -; 벽 마감: -; 이름: 샤프트; 천장 마감: -
공정 - 공정: 새 구성
구속조건 - 베이스 간격띄우기: 0 mm; 상한값: 지상 9층; 레벨: 지상 9층; 한계 간격띄우기: 4500 mm
기타 - 거실여부: no; 공정 ID: 0; 카테고리: 룸; 공간분류코드: 33416; 실ID: 911
에너지 해석 - 구역별 실제 전력 부하: 0; 구역별 실제 조명 부하: 0; 기초 전력 부하: 공간 유형별; 기초 조명 부하: 공간 유형별; 사람 수: 0; 열 부하 값: 공간 유형별; 전력 부하 단위: 전력 밀도; 조명 부하 단위: 전력 밀도; 1인당 잠열 취득: 58.6142 W; 1인당 현열 취득: 73.2678 W; 개인별 면적: 28.5714 m2; 실제 전력 부하: 0 W; 실제 조명 부하: 0 W; 지정된 구역별 전력 부하: 13.9931; 지정된 구역별 조명 부하: 10.7639; 지정된 전력 부하: 0 W; 지정된 조명 부하: 0 W; 천장속 조명 방사: 20; 총 개인별 열 취득: 131.882 W
치수 - 계산 높이: 1000 mm; 둘레: 6800 mm; 면적: 2.08 m2; 무한한 높이: 4500 mm; 체적: 9.36 m3

# IfcSpace: 샤프트 72:5256277, 72
In: 지상 9층
LongName: 샤프트; InteriorOrExteriorSpace: INTERNAL
Pset_SpaceCommon - Reference: 샤프트 72; FloorCovering: -; WallCovering: -; CeilingCovering: -
BaseQuantities - NetFloorArea: 4.80197 m2; Height: 4500 mm; GrossFloorArea: 4.80197 m2; GrossVolume: 21.6089 m3
ID 데이터 - 바닥 마감: -; 번호: 72; 베이스 마감: -; 벽 마감: -; 이름: 샤프트; 천장 마감: -
공정 - 공정: 새 구성
구속조건 - 베이스 간격띄우기: 0 mm; 상한값: 지상 9층; 레벨: 지상 9층; 한계 간격띄우기: 4500 mm
기타 - 거실여부: no; 공정 ID: 0; 카테고리: 룸; 공간분류코드: 33416; 실ID: 912
에너지 해석 - 구역별 실제 전력 부하: 0; 구역별 실제 조명 부하: 0; 기초 전력 부하: 공간 유형별; 기초 조명 부하: 공간 유형별; 사람 수: 0; 열 부하 값: 공간 유형별; 전력 부하 단위: 전력 밀도; 조명 부하 단위: 전력 밀도; 1인당 잠열 취득: 58.6142 W; 1인당 현열 취득: 73.2678 W; 개인별 면적: 28.5714 m2; 실제 전력 부하: 0 W; 실제 조명 부하: 0 W; 지정된 구역별 전력 부하: 13.9931; 지정된 구역별 조명 부하: 10.7639; 지정된 전력 부하: 0 W; 지정된 조명 부하: 0 W; 천장속 조명 방사: 20; 총 개인별 열 취득: 131.882 W
치수 - 계산 높이: 1000 mm; 둘레: 9198.72 mm; 면적: 4.80197 m2; 무한한 높이: 4500 mm; 체적: 21.6086 m3

# IfcSpace: 샤프트 79:5256319, 79
In: 지상 10층
LongName: 샤프트; InteriorOrExteriorSpace: INTERNAL
Pset_SpaceCommon - Reference: 샤프트 79; FloorCovering: -; WallCovering: -; CeilingCovering: -
BaseQuantities - NetFloorArea: 6.40707 m2; Height: 5000 mm; GrossPerimeter: 13754 mm; GrossFloorArea: 6.40707 m2; GrossVolume: 32.0353 m3
ID 데이터 - 바닥 마감: -; 번호: 79; 베이스 마감: -; 벽 마감: -; 이름: 샤프트; 천장 마감: -
공정 - 공정: 새 구성
구속조건 - 베이스 간격띄우기: 0 mm; 상한값: 지상 10층; 레벨: 지상 10층; 한계 간격띄우기: 5000 mm
기타 - 거실여부: no; 공정 ID: 0; 카테고리: 룸; 공간분류코드: 33416; 실ID: 1013
에너지 해석 - 구역별 실제 전력 부하: 0; 구역별 실제 조명 부하: 0; 기초 전력 부하: 공간 유형별; 기초 조명 부하: 공간 유형별; 사람 수: 0; 열 부하 값: 공간 유형별; 전력 부하 단위: 전력 밀도; 조명 부하 단위: 전력 밀도; 1인당 잠열 취득: 58.6142 W; 1인당 현열 취득: 73.2678 W; 개인별 면적: 28.5714 m2; 실제 전력 부하: 0 W; 실제 조명 부하: 0 W; 지정된 구역별 전력 부하: 13.9931; 지정된 구역별 조명 부하: 10.7639; 지정된 전력 부하: 0 W; 지정된 조명 부하: 0 W; 천장속 조명 방사: 20; 총 개인별 열 취득: 131.882 W
치수 - 계산 높이: 1000 mm; 둘레: 13754 mm; 면적: 6.40707 m2; 무한한 높이: 5000 mm; 체적: 32.0353 m3

# IfcSpace: 샤프트 80:5256322, 80
In: 지상 10층
LongName: 샤프트; InteriorOrExteriorSpace: INTERNAL
Pset_SpaceCommon - Reference: 샤프트 80; FloorCovering: -; WallCovering: -; CeilingCovering: -
BaseQuantities - NetFloorArea: 2.06301 m2; Height: 5000 mm; GrossPerimeter: 6761.98 mm; GrossFloorArea: 2.06301 m2; GrossVolume: 10.3151 m3
ID 데이터 - 바닥 마감: -; 번호: 80; 베이스 마감: -; 벽 마감: -; 이름: 샤프트; 천장 마감: -
공정 - 공정: 새 구성
구속조건 - 베이스 간격띄우기: 0 mm; 상한값: 지상 10층; 레벨: 지상 10층; 한계 간격띄우기: 5000 mm
기타 - 거실여부: no; 공정 ID: 0; 카테고리: 룸; 공간분류코드: 33416; 실ID: 1014
에너지 해석 - 구역별 실제 전력 부하: 0; 구역별 실제 조명 부하: 0; 기초 전력 부하: 공간 유형별; 기초 조명 부하: 공간 유형별; 사람 수: 0; 열 부하 값: 공간 유형별; 전력 부하 단위: 전력 밀도; 조명 부하 단위: 전력 밀도; 1인당 잠열 취득: 58.6142 W; 1인당 현열 취득: 73.2678 W; 개인별 면적: 28.5714 m2; 실제 전력 부하: 0 W; 실제 조명 부하: 0 W; 지정된 구역별 전력 부하: 13.9931; 지정된 구역별 조명 부하: 10.7639; 지정된 전력 부하: 0 W; 지정된 조명 부하: 0 W; 천장속 조명 방사: 20; 총 개인별 열 취득: 131.882 W
치수 - 계산 높이: 1000 mm; 둘레: 6761.98 mm; 면적: 2.06301 m2; 무한한 높이: 5000 mm; 체적: 10.3151 m3

# IfcSpace: 샤프트 81:5256325, 81
In: 지상 10층
LongName: 샤프트; InteriorOrExteriorSpace: INTERNAL
Pset_SpaceCommon - Reference: 샤프트 81; FloorCovering: -; WallCovering: -; CeilingCovering: -
BaseQuantities - NetFloorArea: 4.78708 m2; Height: 5000 mm; GrossFloorArea: 4.78708 m2; GrossVolume: 23.9354 m3
ID 데이터 - 바닥 마감: -; 번호: 81; 베이스 마감: -; 벽 마감: -; 이름: 샤프트; 천장 마감: -
공정 - 공정: 새 구성
구속조건 - 베이스 간격띄우기: 0 mm; 상한값: 지상 10층; 레벨: 지상 10층; 한계 간격띄우기: 5000 mm
기타 - 거실여부: no; 공정 ID: 0; 카테고리: 룸; 공간분류코드: 33416; 실ID: 1015
에너지 해석 - 구역별 실제 전력 부하: 0; 구역별 실제 조명 부하: 0; 기초 전력 부하: 공간 유형별; 기초 조명 부하: 공간 유형별; 사람 수: 0; 열 부하 값: 공간 유형별; 전력 부하 단위: 전력 밀도; 조명 부하 단위: 전력 밀도; 1인당 잠열 취득: 58.6142 W; 1인당 현열 취득: 73.2678 W; 개인별 면적: 28.5714 m2; 실제 전력 부하: 0 W; 실제 조명 부하: 0 W; 지정된 구역별 전력 부하: 13.9931; 지정된 구역별 조명 부하: 10.7639; 지정된 전력 부하: 0 W; 지정된 조명 부하: 0 W; 천장속 조명 방사: 20; 총 개인별 열 취득: 131.882 W
치수 - 계산 높이: 1000 mm; 둘레: 9197.97 mm; 면적: 4.78708 m2; 무한한 높이: 5000 mm; 체적: 23.2173 m3

# IfcSpace: 샤프트 82:5256363, 82
In: 옥탑층
LongName: 샤프트; InteriorOrExteriorSpace: INTERNAL
Pset_SpaceCommon - Reference: 샤프트 82; FloorCovering: -; WallCovering: -; CeilingCovering: -
BaseQuantities - NetFloorArea: 6.75277 m2; Height: 4000 mm; GrossPerimeter: 14003.7 mm; GrossFloorArea: 6.75277 m2; GrossVolume: 27.0111 m3
ID 데이터 - 바닥 마감: -; 번호: 82; 베이스 마감: -; 벽 마감: -; 이름: 샤프트; 천장 마감: -
공정 - 공정: 새 구성
구속조건 - 베이스 간격띄우기: 0 mm; 상한값: 옥탑층; 레벨: 옥탑층; 한계 간격띄우기: 4000 mm
기타 - 거실여부: no; 공정 ID: 0; 카테고리: 룸; 공간분류코드: 33416; 실ID: RF08
에너지 해석 - 구역별 실제 전력 부하: 0; 구역별 실제 조명 부하: 0; 기초 전력 부하: 공간 유형별; 기초 조명 부하: 공간 유형별; 사람 수: 0; 열 부하 값: 공간 유형별; 전력 부하 단위: 전력 밀도; 조명 부하 단위: 전력 밀도; 1인당 잠열 취득: 58.6142 W; 1인당 현열 취득: 73.2678 W; 개인별 면적: 28.5714 m2; 실제 전력 부하: 0 W; 실제 조명 부하: 0 W; 지정된 구역별 전력 부하: 13.9931; 지정된 구역별 조명 부하: 10.7639; 지정된 전력 부하: 0 W; 지정된 조명 부하: 0 W; 천장속 조명 방사: 20; 총 개인별 열 취득: 131.882 W
치수 - 계산 높이: 0 mm; 둘레: 14003.7 mm; 면적: 6.75277 m2; 무한한 높이: 4000 mm; 체적: 25.9982 m3

# IfcSpace: 샤프트 84:5256378, 84
In: 옥탑층
LongName: 샤프트; InteriorOrExteriorSpace: INTERNAL
Pset_SpaceCommon - Reference: 샤프트 84; FloorCovering: -; WallCovering: -; CeilingCovering: -
BaseQuantities - NetFloorArea: 2.08 m2; Height: 3850 mm; GrossPerimeter: 6800 mm; GrossFloorArea: 2.08 m2; GrossVolume: 8.008 m3
ID 데이터 - 바닥 마감: -; 번호: 84; 베이스 마감: -; 벽 마감: -; 이름: 샤프트; 천장 마감: -
공정 - 공정: 새 구성
구속조건 - 베이스 간격띄우기: 0 mm; 상한값: 옥탑층; 레벨: 옥탑층; 한계 간격띄우기: 3850 mm
기타 - 거실여부: no; 공정 ID: 0; 카테고리: 룸; 공간분류코드: 33416; 실ID: RF10
에너지 해석 - 구역별 실제 전력 부하: 0; 구역별 실제 조명 부하: 0; 기초 전력 부하: 공간 유형별; 기초 조명 부하: 공간 유형별; 사람 수: 0; 열 부하 값: 공간 유형별; 전력 부하 단위: 전력 밀도; 조명 부하 단위: 전력 밀도; 1인당 잠열 취득: 58.6142 W; 1인당 현열 취득: 73.2678 W; 개인별 면적: 28.5714 m2; 실제 전력 부하: 0 W; 실제 조명 부하: 0 W; 지정된 구역별 전력 부하: 13.9931; 지정된 구역별 조명 부하: 10.7639; 지정된 전력 부하: 0 W; 지정된 조명 부하: 0 W; 천장속 조명 방사: 20; 총 개인별 열 취득: 131.882 W
치수 - 계산 높이: 0 mm; 둘레: 6800 mm; 면적: 2.08 m2; 무한한 높이: 3850 mm; 체적: 8.008 m3

# IfcSpace: 승강기홀 10:5255682, 10
In: 지하2층
LongName: 승강기홀; InteriorOrExteriorSpace: INTERNAL
Pset_SpaceCommon - Reference: 승강기홀 10; FloorCovering: 쇠흙손마감; WallCovering: 수성페인트; CeilingCovering: 지정단열재
BaseQuantities - NetFloorArea: 4.2 m2; Height: 5800 mm; GrossPerimeter: 8200 mm; GrossFloorArea: 4.2 m2; GrossVolume: 24.36 m3
ID 데이터 - 바닥 마감: 쇠흙손마감; 번호: 10; 베이스 마감: 목재 걸레받이; 벽 마감: 수성페인트; 이름: 승강기홀; 천장 마감: 지정단열재
공정 - 공정: 새 구성
구속조건 - 상한값: 지하2층; 레벨: 지하2층; 베이스 간격띄우기: -1800 mm; 한계 간격띄우기: 4000 mm
기타 - 거실여부: no; 공정 ID: 0; 카테고리: 룸; 공간분류코드: 33109; 실ID: B214
에너지 해석 - 구역별 실제 전력 부하: 0; 구역별 실제 조명 부하: 0; 기초 전력 부하: 공간 유형별; 기초 조명 부하: 공간 유형별; 사람 수: 0; 열 부하 값: 공간 유형별; 전력 부하 단위: 전력 밀도; 조명 부하 단위: 전력 밀도; 1인당 잠열 취득: 58.6142 W; 1인당 현열 취득: 73.2678 W; 개인별 면적: 28.5714 m2; 실제 전력 부하: 0 W; 실제 조명 부하: 0 W; 지정된 구역별 전력 부하: 13.9931; 지정된 구역별 조명 부하: 10.7639; 지정된 전력 부하: 0 W; 지정된 조명 부하: 0 W; 천장속 조명 방사: 20; 총 개인별 열 취득: 131.882 W
치수 - 계산 높이: 0 mm; 둘레: 8200 mm; 면적: 4.2 m2; 무한한 높이: 5800 mm; 체적: 24.36 m3

# IfcSpace: 승강기홀 13:5255760, 13
In: 지하1층
LongName: 승강기홀; InteriorOrExteriorSpace: INTERNAL
Pset_SpaceCommon - Reference: 승강기홀 13; FloorCovering: 쇠흙손마감; WallCovering: 수성페인트; CeilingCovering: 지정단열재
BaseQuantities - NetFloorArea: 6.2644 m2; Height: 6100 mm; GrossPerimeter: 10011.5 mm; GrossFloorArea: 6.2644 m2; GrossVolume: 38.2128 m3
ID 데이터 - 바닥 마감: 쇠흙손마감; 번호: 13; 베이스 마감: 목재 걸레받이; 벽 마감: 수성페인트; 이름: 승강기홀; 천장 마감: 지정단열재
공정 - 공정: 새 구성
구속조건 - 베이스 간격띄우기: 0 mm; 상한값: 지하1층; 레벨: 지하1층; 한계 간격띄우기: 6100 mm
기타 - 거실여부: no; 공정 ID: 0; 카테고리: 룸; 공간분류코드: 33109; 실ID: B111
에너지 해석 - 구역별 실제 전력 부하: 0; 구역별 실제 조명 부하: 0; 기초 전력 부하: 공간 유형별; 기초 조명 부하: 공간 유형별; 사람 수: 0; 열 부하 값: 공간 유형별; 전력 부하 단위: 전력 밀도; 조명 부하 단위: 전력 밀도; 1인당 잠열 취득: 58.6142 W; 1인당 현열 취득: 73.2678 W; 개인별 면적: 28.5714 m2; 실제 전력 부하: 0 W; 실제 조명 부하: 0 W; 지정된 구역별 전력 부하: 13.9931; 지정된 구역별 조명 부하: 10.7639; 지정된 전력 부하: 0 W; 지정된 조명 부하: 0 W; 천장속 조명 방사: 20; 총 개인별 열 취득: 131.882 W
치수 - 계산 높이: 0 mm; 둘레: 10011.5 mm; 면적: 6.2644 m2; 무한한 높이: 6100 mm; 체적: 38.2128 m3

# IfcSpace: 승강기홀 14:5255763, 14
In: 지하1층
LongName: 승강기홀; InteriorOrExteriorSpace: INTERNAL
Pset_SpaceCommon - Reference: 승강기홀 14; FloorCovering: 쇠흙손마감; WallCovering: 수성페인트; CeilingCovering: 지정단열재
BaseQuantities - NetFloorArea: 8.41095 m2; Height: 6100 mm; GrossPerimeter: 11607.8 mm; GrossFloorArea: 8.41095 m2; GrossVolume: 51.3068 m3
ID 데이터 - 바닥 마감: 쇠흙손마감; 번호: 14; 베이스 마감: 목재 걸레받이; 벽 마감: 수성페인트; 이름: 승강기홀; 천장 마감: 지정단열재
공정 - 공정: 새 구성
구속조건 - 베이스 간격띄우기: 0 mm; 상한값: 지하1층; 레벨: 지하1층; 한계 간격띄우기: 6100 mm
기타 - 거실여부: no; 공정 ID: 0; 카테고리: 룸; 공간분류코드: 33109; 실ID: B112
에너지 해석 - 구역별 실제 전력 부하: 0; 구역별 실제 조명 부하: 0; 기초 전력 부하: 공간 유형별; 기초 조명 부하: 공간 유형별; 사람 수: 0; 열 부하 값: 공간 유형별; 전력 부하 단위: 전력 밀도; 조명 부하 단위: 전력 밀도; 1인당 잠열 취득: 58.6142 W; 1인당 현열 취득: 73.2678 W; 개인별 면적: 28.5714 m2; 실제 전력 부하: 0 W; 실제 조명 부하: 0 W; 지정된 구역별 전력 부하: 13.9931; 지정된 구역별 조명 부하: 10.7639; 지정된 전력 부하: 0 W; 지정된 조명 부하: 0 W; 천장속 조명 방사: 20; 총 개인별 열 취득: 131.882 W
치수 - 계산 높이: 0 mm; 둘레: 11607.8 mm; 면적: 8.41095 m2; 무한한 높이: 6100 mm; 체적: 51.3068 m3

# IfcSpace: 승강기홀 15:5255766, 15
In: 지하1층
LongName: 승강기홀; InteriorOrExteriorSpace: INTERNAL
Pset_SpaceCommon - Reference: 승강기홀 15; FloorCovering: 쇠흙손마감; WallCovering: 수성페인트; CeilingCovering: 지정단열재
BaseQuantities - NetFloorArea: 4.2 m2; Height: 6100 mm; GrossPerimeter: 8200 mm; GrossFloorArea: 4.2 m2; GrossVolume: 25.62 m3
ID 데이터 - 바닥 마감: 쇠흙손마감; 번호: 15; 베이스 마감: 목재 걸레받이; 벽 마감: 수성페인트; 이름: 승강기홀; 천장 마감: 지정단열재
공정 - 공정: 새 구성
구속조건 - 베이스 간격띄우기: 0 mm; 상한값: 지하1층; 레벨: 지하1층; 한계 간격띄우기: 6100 mm
기타 - 거실여부: no; 공정 ID: 0; 카테고리: 룸; 공간분류코드: 33109; 실ID: B113
에너지 해석 - 구역별 실제 전력 부하: 0; 구역별 실제 조명 부하: 0; 기초 전력 부하: 공간 유형별; 기초 조명 부하: 공간 유형별; 사람 수: 0; 열 부하 값: 공간 유형별; 전력 부하 단위: 전력 밀도; 조명 부하 단위: 전력 밀도; 1인당 잠열 취득: 58.6142 W; 1인당 현열 취득: 73.2678 W; 개인별 면적: 28.5714 m2; 실제 전력 부하: 0 W; 실제 조명 부하: 0 W; 지정된 구역별 전력 부하: 13.9931; 지정된 구역별 조명 부하: 10.7639; 지정된 전력 부하: 0 W; 지정된 조명 부하: 0 W; 천장속 조명 방사: 20; 총 개인별 열 취득: 131.882 W
치수 - 계산 높이: 0 mm; 둘레: 8200 mm; 면적: 4.2 m2; 무한한 높이: 6100 mm; 체적: 25.62 m3

# IfcSpace: 승강기홀 18:5255821, 18
In: 지상 1층
LongName: 승강기홀; InteriorOrExteriorSpace: INTERNAL
Pset_SpaceCommon - Reference: 승강기홀 18; FloorCovering: 쇠흙손마감; WallCovering: 수성페인트; CeilingCovering: 지정단열재
BaseQuantities - NetFloorArea: 6.2644 m2; Height: 4800 mm; GrossFloorArea: 6.2644 m2; GrossVolume: 30.0691 m3
ID 데이터 - 바닥 마감: 쇠흙손마감; 번호: 18; 베이스 마감: 목재 걸레받이; 벽 마감: 수성페인트; 이름: 승강기홀; 천장 마감: 지정단열재
공정 - 공정: 새 구성
구속조건 - 베이스 간격띄우기: 0 mm; 상한값: 지상 1층; 레벨: 지상 1층; 한계 간격띄우기: 4800 mm
기타 - 거실여부: no; 공정 ID: 0; 카테고리: 룸; 공간분류코드: 33109; 실ID: 124
에너지 해석 - 구역별 실제 전력 부하: 0; 구역별 실제 조명 부하: 0; 기초 전력 부하: 공간 유형별; 기초 조명 부하: 공간 유형별; 사람 수: 0; 열 부하 값: 공간 유형별; 전력 부하 단위: 전력 밀도; 조명 부하 단위: 전력 밀도; 1인당 잠열 취득: 58.6142 W; 1인당 현열 취득: 73.2678 W; 개인별 면적: 28.5714 m2; 실제 전력 부하: 0 W; 실제 조명 부하: 0 W; 지정된 구역별 전력 부하: 13.9931; 지정된 구역별 조명 부하: 10.7639; 지정된 전력 부하: 0 W; 지정된 조명 부하: 0 W; 천장속 조명 방사: 20; 총 개인별 열 취득: 131.882 W
치수 - 계산 높이: 1000 mm; 둘레: 10011.5 mm; 면적: 6.2644 m2; 무한한 높이: 4800 mm; 체적: 30.067 m3

# IfcSpace: 승강기홀 19:5255824, 19
In: 지상 1층
LongName: 승강기홀; InteriorOrExteriorSpace: INTERNAL
Pset_SpaceCommon - Reference: 승강기홀 19; FloorCovering: 쇠흙손마감; WallCovering: 수성페인트; CeilingCovering: 지정단열재
BaseQuantities - NetFloorArea: 8.41095 m2; Height: 4800 mm; GrossFloorArea: 8.41095 m2; GrossVolume: 40.3725 m3
ID 데이터 - 바닥 마감: 쇠흙손마감; 번호: 19; 베이스 마감: 목재 걸레받이; 벽 마감: 수성페인트; 이름: 승강기홀; 천장 마감: 지정단열재
공정 - 공정: 새 구성
구속조건 - 베이스 간격띄우기: 0 mm; 상한값: 지상 1층; 레벨: 지상 1층; 한계 간격띄우기: 4800 mm
기타 - 거실여부: no; 공정 ID: 0; 카테고리: 룸; 공간분류코드: 33109; 실ID: 125
에너지 해석 - 구역별 실제 전력 부하: 0; 구역별 실제 조명 부하: 0; 기초 전력 부하: 공간 유형별; 기초 조명 부하: 공간 유형별; 사람 수: 0; 열 부하 값: 공간 유형별; 전력 부하 단위: 전력 밀도; 조명 부하 단위: 전력 밀도; 1인당 잠열 취득: 58.6142 W; 1인당 현열 취득: 73.2678 W; 개인별 면적: 28.5714 m2; 실제 전력 부하: 0 W; 실제 조명 부하: 0 W; 지정된 구역별 전력 부하: 13.9931; 지정된 구역별 조명 부하: 10.7639; 지정된 전력 부하: 0 W; 지정된 조명 부하: 0 W; 천장속 조명 방사: 20; 총 개인별 열 취득: 131.882 W
치수 - 계산 높이: 1000 mm; 둘레: 11607.8 mm; 면적: 8.41095 m2; 무한한 높이: 4800 mm; 체적: 40.3709 m3

# IfcSpace: 승강기홀 20:5255827, 20
In: 지상 1층
LongName: 승강기홀; InteriorOrExteriorSpace: INTERNAL
Pset_SpaceCommon - Reference: 승강기홀 20; FloorCovering: 쇠흙손마감; WallCovering: 수성페인트; CeilingCovering: 지정단열재
BaseQuantities - NetFloorArea: 4.2 m2; Height: 4800 mm; GrossPerimeter: 8200 mm; GrossFloorArea: 4.2 m2; GrossVolume: 20.16 m3
ID 데이터 - 바닥 마감: 쇠흙손마감; 번호: 20; 베이스 마감: 목재 걸레받이; 벽 마감: 수성페인트; 이름: 승강기홀; 천장 마감: 지정단열재
공정 - 공정: 새 구성
구속조건 - 베이스 간격띄우기: 0 mm; 상한값: 지상 1층; 레벨: 지상 1층; 한계 간격띄우기: 4800 mm
기타 - 거실여부: no; 공정 ID: 0; 카테고리: 룸; 공간분류코드: 33109; 실ID: 126
에너지 해석 - 구역별 실제 전력 부하: 0; 구역별 실제 조명 부하: 0; 기초 전력 부하: 공간 유형별; 기초 조명 부하: 공간 유형별; 사람 수: 0; 열 부하 값: 공간 유형별; 전력 부하 단위: 전력 밀도; 조명 부하 단위: 전력 밀도; 1인당 잠열 취득: 58.6142 W; 1인당 현열 취득: 73.2678 W; 개인별 면적: 28.5714 m2; 실제 전력 부하: 0 W; 실제 조명 부하: 0 W; 지정된 구역별 전력 부하: 13.9931; 지정된 구역별 조명 부하: 10.7639; 지정된 전력 부하: 0 W; 지정된 조명 부하: 0 W; 천장속 조명 방사: 20; 총 개인별 열 취득: 131.882 W
치수 - 계산 높이: 1000 mm; 둘레: 8200 mm; 면적: 4.2 m2; 무한한 높이: 4800 mm; 체적: 20.16 m3

# IfcSpace: 승강기홀 26:5255951, 26
In: 지상 2층
LongName: 승강기홀; InteriorOrExteriorSpace: INTERNAL
Pset_SpaceCommon - Reference: 승강기홀 26; FloorCovering: 쇠흙손마감; WallCovering: 수성페인트; CeilingCovering: 지정단열재
BaseQuantities - NetFloorArea: 6.2598 m2; Height: 4500 mm; GrossFloorArea: 6.2598 m2; GrossVolume: 28.1691 m3
ID 데이터 - 바닥 마감: 쇠흙손마감; 번호: 26; 베이스 마감: 목재 걸레받이; 벽 마감: 수성페인트; 이름: 승강기홀; 천장 마감: 지정단열재
공정 - 공정: 새 구성
구속조건 - 베이스 간격띄우기: 0 mm; 상한값: 지상 2층; 레벨: 지상 2층; 한계 간격띄우기: 4500 mm
기타 - 거실여부: no; 공정 ID: 0; 카테고리: 룸; 공간분류코드: 33109; 실ID: 213
에너지 해석 - 구역별 실제 전력 부하: 0; 구역별 실제 조명 부하: 0; 기초 전력 부하: 공간 유형별; 기초 조명 부하: 공간 유형별; 사람 수: 0; 열 부하 값: 공간 유형별; 전력 부하 단위: 전력 밀도; 조명 부하 단위: 전력 밀도; 1인당 잠열 취득: 58.6142 W; 1인당 현열 취득: 73.2678 W; 개인별 면적: 28.5714 m2; 실제 전력 부하: 0 W; 실제 조명 부하: 0 W; 지정된 구역별 전력 부하: 13.9931; 지정된 구역별 조명 부하: 10.7639; 지정된 전력 부하: 0 W; 지정된 조명 부하: 0 W; 천장속 조명 방사: 20; 총 개인별 열 취득: 131.882 W
치수 - 계산 높이: 1000 mm; 둘레: 10007.8 mm; 면적: 6.2598 m2; 무한한 높이: 4500 mm; 체적: 28.1676 m3

# IfcSpace: 승강기홀 27:5255954, 27
In: 지상 2층
LongName: 승강기홀; InteriorOrExteriorSpace: INTERNAL
Pset_SpaceCommon - Reference: 승강기홀 27; FloorCovering: 쇠흙손마감; WallCovering: 수성페인트; CeilingCovering: 지정단열재
BaseQuantities - NetFloorArea: 8.41095 m2; Height: 4500 mm; GrossFloorArea: 8.41095 m2; GrossVolume: 37.8493 m3
ID 데이터 - 바닥 마감: 쇠흙손마감; 번호: 27; 베이스 마감: 목재 걸레받이; 벽 마감: 수성페인트; 이름: 승강기홀; 천장 마감: 지정단열재
공정 - 공정: 새 구성
구속조건 - 베이스 간격띄우기: 0 mm; 상한값: 지상 2층; 레벨: 지상 2층; 한계 간격띄우기: 4500 mm
기타 - 거실여부: no; 공정 ID: 0; 카테고리: 룸; 공간분류코드: 33109; 실ID: 214
에너지 해석 - 구역별 실제 전력 부하: 0; 구역별 실제 조명 부하: 0; 기초 전력 부하: 공간 유형별; 기초 조명 부하: 공간 유형별; 사람 수: 0; 열 부하 값: 공간 유형별; 전력 부하 단위: 전력 밀도; 조명 부하 단위: 전력 밀도; 1인당 잠열 취득: 58.6142 W; 1인당 현열 취득: 73.2678 W; 개인별 면적: 28.5714 m2; 실제 전력 부하: 0 W; 실제 조명 부하: 0 W; 지정된 구역별 전력 부하: 13.9931; 지정된 구역별 조명 부하: 10.7639; 지정된 전력 부하: 0 W; 지정된 조명 부하: 0 W; 천장속 조명 방사: 20; 총 개인별 열 취득: 131.882 W
치수 - 계산 높이: 1000 mm; 둘레: 11607.8 mm; 면적: 8.41095 m2; 무한한 높이: 4500 mm; 체적: 37.8476 m3

# IfcSpace: 승강기홀 28:5255957, 28
In: 지상 2층
LongName: 승강기홀; InteriorOrExteriorSpace: INTERNAL
Pset_SpaceCommon - Reference: 승강기홀 28; FloorCovering: 쇠흙손마감; WallCovering: 수성페인트; CeilingCovering: 지정단열재
BaseQuantities - NetFloorArea: 4.2 m2; Height: 4500 mm; GrossPerimeter: 8200 mm; GrossFloorArea: 4.2 m2; GrossVolume: 18.9 m3
ID 데이터 - 바닥 마감: 쇠흙손마감; 번호: 28; 베이스 마감: 목재 걸레받이; 벽 마감: 수성페인트; 이름: 승강기홀; 천장 마감: 지정단열재
공정 - 공정: 새 구성
구속조건 - 베이스 간격띄우기: 0 mm; 상한값: 지상 2층; 레벨: 지상 2층; 한계 간격띄우기: 4500 mm
기타 - 거실여부: no; 공정 ID: 0; 카테고리: 룸; 공간분류코드: 33109; 실ID: 215
에너지 해석 - 구역별 실제 전력 부하: 0; 구역별 실제 조명 부하: 0; 기초 전력 부하: 공간 유형별; 기초 조명 부하: 공간 유형별; 사람 수: 0; 열 부하 값: 공간 유형별; 전력 부하 단위: 전력 밀도; 조명 부하 단위: 전력 밀도; 1인당 잠열 취득: 58.6142 W; 1인당 현열 취득: 73.2678 W; 개인별 면적: 28.5714 m2; 실제 전력 부하: 0 W; 실제 조명 부하: 0 W; 지정된 구역별 전력 부하: 13.9931; 지정된 구역별 조명 부하: 10.7639; 지정된 전력 부하: 0 W; 지정된 조명 부하: 0 W; 천장속 조명 방사: 20; 총 개인별 열 취득: 131.882 W
치수 - 계산 높이: 1000 mm; 둘레: 8200 mm; 면적: 4.2 m2; 무한한 높이: 4500 mm; 체적: 18.9 m3

# IfcSpace: 승강기홀 320:3695661, 320
In: 옥탑층
LongName: 승강기홀; InteriorOrExteriorSpace: INTERNAL
Pset_SpaceCommon - Reference: 승강기홀 320; FloorCovering: 쇠흙손마감; WallCovering: 수성페인트; CeilingCovering: 지정단열재
BaseQuantities - NetFloorArea: 6.2644 m2; Height: 3850 mm; GrossPerimeter: 10011.5 mm; GrossFloorArea: 6.2644 m2; GrossVolume: 24.1179 m3
ID 데이터 - 바닥 마감: 쇠흙손마감; 번호: 320; 베이스 마감: 목재 걸레받이; 벽 마감: 수성페인트; 이름: 승강기홀; 천장 마감: 지정단열재
공정 - 공정: 새 구성
구속조건 - 베이스 간격띄우기: 0 mm; 상한값: 옥탑층; 레벨: 옥탑층; 한계 간격띄우기: 3850 mm
기타 - 거실여부: no; 공정 ID: 0; 카테고리: 룸; 공간분류코드: 33109; 실ID: RF03
에너지 해석 - 구역별 실제 전력 부하: 0; 구역별 실제 조명 부하: 0; 기초 전력 부하: 공간 유형별; 기초 조명 부하: 공간 유형별; 사람 수: 0; 열 부하 값: 공간 유형별; 전력 부하 단위: 전력 밀도; 조명 부하 단위: 전력 밀도; 1인당 잠열 취득: 58.6142 W; 1인당 현열 취득: 73.2678 W; 개인별 면적: 28.5714 m2; 실제 전력 부하: 0 W; 실제 조명 부하: 0 W; 지정된 구역별 전력 부하: 13.9931; 지정된 구역별 조명 부하: 10.7639; 지정된 전력 부하: 0 W; 지정된 조명 부하: 0 W; 천장속 조명 방사: 20; 총 개인별 열 취득: 131.882 W
치수 - 계산 높이: 0 mm; 둘레: 10011.5 mm; 면적: 6.2644 m2; 무한한 높이: 3850 mm; 체적: 24.1179 m3

# IfcSpace: 승강기홀 321:3695664, 321
In: 옥탑층
LongName: 승강기홀; InteriorOrExteriorSpace: INTERNAL
Pset_SpaceCommon - Reference: 승강기홀 321; FloorCovering: 쇠흙손마감; WallCovering: 수성페인트; CeilingCovering: 지정단열재
BaseQuantities - NetFloorArea: 8.41095 m2; Height: 3850 mm; GrossPerimeter: 11607.8 mm; GrossFloorArea: 8.41095 m2; GrossVolume: 32.3821 m3
ID 데이터 - 바닥 마감: 쇠흙손마감; 번호: 321; 베이스 마감: 목재 걸레받이; 벽 마감: 수성페인트; 이름: 승강기홀; 천장 마감: 지정단열재
공정 - 공정: 새 구성
구속조건 - 베이스 간격띄우기: 0 mm; 상한값: 옥탑층; 레벨: 옥탑층; 한계 간격띄우기: 3850 mm
기타 - 거실여부: no; 공정 ID: 0; 카테고리: 룸; 공간분류코드: 33109; 실ID: RF04
에너지 해석 - 구역별 실제 전력 부하: 0; 구역별 실제 조명 부하: 0; 기초 전력 부하: 공간 유형별; 기초 조명 부하: 공간 유형별; 사람 수: 0; 열 부하 값: 공간 유형별; 전력 부하 단위: 전력 밀도; 조명 부하 단위: 전력 밀도; 1인당 잠열 취득: 58.6142 W; 1인당 현열 취득: 73.2678 W; 개인별 면적: 28.5714 m2; 실제 전력 부하: 0 W; 실제 조명 부하: 0 W; 지정된 구역별 전력 부하: 13.9931; 지정된 구역별 조명 부하: 10.7639; 지정된 전력 부하: 0 W; 지정된 조명 부하: 0 W; 천장속 조명 방사: 20; 총 개인별 열 취득: 131.882 W
치수 - 계산 높이: 0 mm; 둘레: 11607.8 mm; 면적: 8.41095 m2; 무한한 높이: 3850 mm; 체적: 32.3821 m3

# IfcSpace: 승강기홀 322:3695667, 322
In: 옥탑층
LongName: 승강기홀; InteriorOrExteriorSpace: INTERNAL
Pset_SpaceCommon - Reference: 승강기홀 322; FloorCovering: 쇠흙손마감; WallCovering: 수성페인트; CeilingCovering: 지정단열재
BaseQuantities - NetFloorArea: 4.2 m2; Height: 3850 mm; GrossPerimeter: 8200 mm; GrossFloorArea: 4.2 m2; GrossVolume: 16.17 m3
ID 데이터 - 바닥 마감: 쇠흙손마감; 번호: 322; 베이스 마감: 목재 걸레받이; 벽 마감: 수성페인트; 이름: 승강기홀; 천장 마감: 지정단열재
공정 - 공정: 새 구성
구속조건 - 베이스 간격띄우기: 0 mm; 상한값: 옥탑층; 레벨: 옥탑층; 한계 간격띄우기: 3850 mm
기타 - 거실여부: no; 공정 ID: 0; 카테고리: 룸; 공간분류코드: 33109; 실ID: RF05
에너지 해석 - 구역별 실제 전력 부하: 0; 구역별 실제 조명 부하: 0; 기초 전력 부하: 공간 유형별; 기초 조명 부하: 공간 유형별; 사람 수: 0; 열 부하 값: 공간 유형별; 전력 부하 단위: 전력 밀도; 조명 부하 단위: 전력 밀도; 1인당 잠열 취득: 58.6142 W; 1인당 현열 취득: 73.2678 W; 개인별 면적: 28.5714 m2; 실제 전력 부하: 0 W; 실제 조명 부하: 0 W; 지정된 구역별 전력 부하: 13.9931; 지정된 구역별 조명 부하: 10.7639; 지정된 전력 부하: 0 W; 지정된 조명 부하: 0 W; 천장속 조명 방사: 20; 총 개인별 열 취득: 131.882 W
치수 - 계산 높이: 0 mm; 둘레: 8200 mm; 면적: 4.2 m2; 무한한 높이: 3850 mm; 체적: 16.17 m3

# IfcSpace: 승강기홀 36:5256044, 36
In: 지상 3층
LongName: 승강기홀; InteriorOrExteriorSpace: INTERNAL
Pset_SpaceCommon - Reference: 승강기홀 36; FloorCovering: 쇠흙손마감; WallCovering: 무늬코트뿜칠; CeilingCovering: 지정단열재
BaseQuantities - NetFloorArea: 6.2498 m2; Height: 4100 mm; GrossPerimeter: 9999.84 mm; GrossFloorArea: 6.2498 m2; GrossVolume: 25.6242 m3
ID 데이터 - 바닥 마감: 쇠흙손마감; 번호: 36; 베이스 마감: 목재 걸레받이; 벽 마감: 무늬코트뿜칠; 이름: 승강기홀; 천장 마감: 지정단열재
공정 - 공정: 새 구성
구속조건 - 베이스 간격띄우기: 0 mm; 상한값: 지상 3층; 레벨: 지상 3층; 한계 간격띄우기: 4100 mm
기타 - 거실여부: no; 공정 ID: 0; 카테고리: 룸; 공간분류코드: 33109; 실ID: 317
에너지 해석 - 구역별 실제 전력 부하: 0; 구역별 실제 조명 부하: 0; 기초 전력 부하: 공간 유형별; 기초 조명 부하: 공간 유형별; 사람 수: 0; 열 부하 값: 공간 유형별; 전력 부하 단위: 전력 밀도; 조명 부하 단위: 전력 밀도; 1인당 잠열 취득: 58.6142 W; 1인당 현열 취득: 73.2678 W; 개인별 면적: 28.5714 m2; 실제 전력 부하: 0 W; 실제 조명 부하: 0 W; 지정된 구역별 전력 부하: 13.9931; 지정된 구역별 조명 부하: 10.7639; 지정된 전력 부하: 0 W; 지정된 조명 부하: 0 W; 천장속 조명 방사: 20; 총 개인별 열 취득: 131.882 W
치수 - 계산 높이: 1000 mm; 둘레: 9999.84 mm; 면적: 6.2498 m2; 무한한 높이: 4100 mm; 체적: 25.6242 m3

# IfcSpace: 승강기홀 37:5256047, 37
In: 지상 3층
LongName: 승강기홀; InteriorOrExteriorSpace: INTERNAL
Pset_SpaceCommon - Reference: 승강기홀 37; FloorCovering: 쇠흙손마감; WallCovering: 무늬코트뿜칠; CeilingCovering: 지정단열재
BaseQuantities - NetFloorArea: 8.39975 m2; Height: 4100 mm; GrossPerimeter: 11599.8 mm; GrossFloorArea: 8.39975 m2; GrossVolume: 34.439 m3
ID 데이터 - 바닥 마감: 쇠흙손마감; 번호: 37; 베이스 마감: 목재 걸레받이; 벽 마감: 무늬코트뿜칠; 이름: 승강기홀; 천장 마감: 지정단열재
공정 - 공정: 새 구성
구속조건 - 베이스 간격띄우기: 0 mm; 상한값: 지상 3층; 레벨: 지상 3층; 한계 간격띄우기: 4100 mm
기타 - 거실여부: no; 공정 ID: 0; 카테고리: 룸; 공간분류코드: 33109; 실ID: 318
에너지 해석 - 구역별 실제 전력 부하: 0; 구역별 실제 조명 부하: 0; 기초 전력 부하: 공간 유형별; 기초 조명 부하: 공간 유형별; 사람 수: 0; 열 부하 값: 공간 유형별; 전력 부하 단위: 전력 밀도; 조명 부하 단위: 전력 밀도; 1인당 잠열 취득: 58.6142 W; 1인당 현열 취득: 73.2678 W; 개인별 면적: 28.5714 m2; 실제 전력 부하: 0 W; 실제 조명 부하: 0 W; 지정된 구역별 전력 부하: 13.9931; 지정된 구역별 조명 부하: 10.7639; 지정된 전력 부하: 0 W; 지정된 조명 부하: 0 W; 천장속 조명 방사: 20; 총 개인별 열 취득: 131.882 W
치수 - 계산 높이: 1000 mm; 둘레: 11599.8 mm; 면적: 8.39975 m2; 무한한 높이: 4100 mm; 체적: 34.439 m3

# IfcSpace: 승강기홀 38:5256050, 38
In: 지상 3층
LongName: 승강기홀; InteriorOrExteriorSpace: INTERNAL
Pset_SpaceCommon - Reference: 승강기홀 38; FloorCovering: 쇠흙손마감; WallCovering: 무늬코트뿜칠; CeilingCovering: 지정단열재
BaseQuantities - NetFloorArea: 4.2 m2; Height: 4100 mm; GrossPerimeter: 8200 mm; GrossFloorArea: 4.2 m2; GrossVolume: 17.22 m3
ID 데이터 - 바닥 마감: 쇠흙손마감; 번호: 38; 베이스 마감: 목재 걸레받이; 벽 마감: 무늬코트뿜칠; 이름: 승강기홀; 천장 마감: 지정단열재
공정 - 공정: 새 구성
구속조건 - 베이스 간격띄우기: 0 mm; 상한값: 지상 3층; 레벨: 지상 3층; 한계 간격띄우기: 4100 mm
기타 - 거실여부: no; 공정 ID: 0; 카테고리: 룸; 공간분류코드: 33109; 실ID: 319
에너지 해석 - 구역별 실제 전력 부하: 0; 구역별 실제 조명 부하: 0; 기초 전력 부하: 공간 유형별; 기초 조명 부하: 공간 유형별; 사람 수: 0; 열 부하 값: 공간 유형별; 전력 부하 단위: 전력 밀도; 조명 부하 단위: 전력 밀도; 1인당 잠열 취득: 58.6142 W; 1인당 현열 취득: 73.2678 W; 개인별 면적: 28.5714 m2; 실제 전력 부하: 0 W; 실제 조명 부하: 0 W; 지정된 구역별 전력 부하: 13.9931; 지정된 구역별 조명 부하: 10.7639; 지정된 전력 부하: 0 W; 지정된 조명 부하: 0 W; 천장속 조명 방사: 20; 총 개인별 열 취득: 131.882 W
치수 - 계산 높이: 1000 mm; 둘레: 8200 mm; 면적: 4.2 m2; 무한한 높이: 4100 mm; 체적: 17.22 m3

# IfcSpace: 승강기홀 39:5256064, 39
In: 지상 4층
LongName: 승강기홀; InteriorOrExteriorSpace: INTERNAL
Pset_SpaceCommon - Reference: 승강기홀 39; FloorCovering: 쇠흙손마감; WallCovering: 무늬코트뿜칠; CeilingCovering: 지정단열재
BaseQuantities - NetFloorArea: 6.24999 m2; Height: 4100 mm; GrossPerimeter: 9999.99 mm; GrossFloorArea: 6.24999 m2; GrossVolume: 25.6249 m3
ID 데이터 - 바닥 마감: 쇠흙손마감; 번호: 39; 베이스 마감: 목재 걸레받이; 벽 마감: 무늬코트뿜칠; 이름: 승강기홀; 천장 마감: 지정단열재
공정 - 공정: 새 구성
구속조건 - 베이스 간격띄우기: 0 mm; 상한값: 지상 4층; 레벨: 지상 4층; 한계 간격띄우기: 4100 mm
기타 - 거실여부: no; 공정 ID: 0; 카테고리: 룸; 공간분류코드: 33109; 실ID: 413
에너지 해석 - 구역별 실제 전력 부하: 0; 구역별 실제 조명 부하: 0; 기초 전력 부하: 공간 유형별; 기초 조명 부하: 공간 유형별; 사람 수: 0; 열 부하 값: 공간 유형별; 전력 부하 단위: 전력 밀도; 조명 부하 단위: 전력 밀도; 1인당 잠열 취득: 58.6142 W; 1인당 현열 취득: 73.2678 W; 개인별 면적: 28.5714 m2; 실제 전력 부하: 0 W; 실제 조명 부하: 0 W; 지정된 구역별 전력 부하: 13.9931; 지정된 구역별 조명 부하: 10.7639; 지정된 전력 부하: 0 W; 지정된 조명 부하: 0 W; 천장속 조명 방사: 20; 총 개인별 열 취득: 131.882 W
치수 - 계산 높이: 1000 mm; 둘레: 9999.99 mm; 면적: 6.24999 m2; 무한한 높이: 4100 mm; 체적: 25.6249 m3

# IfcSpace: 승강기홀 40:5256067, 40
In: 지상 4층
LongName: 승강기홀; InteriorOrExteriorSpace: INTERNAL
Pset_SpaceCommon - Reference: 승강기홀 40; FloorCovering: 쇠흙손마감; WallCovering: 무늬코트뿜칠; CeilingCovering: 지정단열재
BaseQuantities - NetFloorArea: 8.39952 m2; Height: 4100 mm; GrossPerimeter: 11599.7 mm; GrossFloorArea: 8.39952 m2; GrossVolume: 34.438 m3
ID 데이터 - 바닥 마감: 쇠흙손마감; 번호: 40; 베이스 마감: 목재 걸레받이; 벽 마감: 무늬코트뿜칠; 이름: 승강기홀; 천장 마감: 지정단열재
공정 - 공정: 새 구성
구속조건 - 베이스 간격띄우기: 0 mm; 상한값: 지상 4층; 레벨: 지상 4층; 한계 간격띄우기: 4100 mm
기타 - 거실여부: no; 공정 ID: 0; 카테고리: 룸; 공간분류코드: 33109; 실ID: 414
에너지 해석 - 구역별 실제 전력 부하: 0; 구역별 실제 조명 부하: 0; 기초 전력 부하: 공간 유형별; 기초 조명 부하: 공간 유형별; 사람 수: 0; 열 부하 값: 공간 유형별; 전력 부하 단위: 전력 밀도; 조명 부하 단위: 전력 밀도; 1인당 잠열 취득: 58.6142 W; 1인당 현열 취득: 73.2678 W; 개인별 면적: 28.5714 m2; 실제 전력 부하: 0 W; 실제 조명 부하: 0 W; 지정된 구역별 전력 부하: 13.9931; 지정된 구역별 조명 부하: 10.7639; 지정된 전력 부하: 0 W; 지정된 조명 부하: 0 W; 천장속 조명 방사: 20; 총 개인별 열 취득: 131.882 W
치수 - 계산 높이: 1000 mm; 둘레: 11599.7 mm; 면적: 8.39952 m2; 무한한 높이: 4100 mm; 체적: 34.438 m3

# IfcSpace: 승강기홀 41:5256070, 41
In: 지상 4층
LongName: 승강기홀; InteriorOrExteriorSpace: INTERNAL
Pset_SpaceCommon - Reference: 승강기홀 41; FloorCovering: 쇠흙손마감; WallCovering: 무늬코트뿜칠; CeilingCovering: 지정단열재
BaseQuantities - NetFloorArea: 4.2 m2; Height: 4100 mm; GrossPerimeter: 8200 mm; GrossFloorArea: 4.2 m2; GrossVolume: 17.22 m3
ID 데이터 - 바닥 마감: 쇠흙손마감; 번호: 41; 베이스 마감: 목재 걸레받이; 벽 마감: 무늬코트뿜칠; 이름: 승강기홀; 천장 마감: 지정단열재
공정 - 공정: 새 구성
구속조건 - 베이스 간격띄우기: 0 mm; 상한값: 지상 4층; 레벨: 지상 4층; 한계 간격띄우기: 4100 mm
기타 - 거실여부: no; 공정 ID: 0; 카테고리: 룸; 공간분류코드: 33109; 실ID: 415
에너지 해석 - 구역별 실제 전력 부하: 0; 구역별 실제 조명 부하: 0; 기초 전력 부하: 공간 유형별; 기초 조명 부하: 공간 유형별; 사람 수: 0; 열 부하 값: 공간 유형별; 전력 부하 단위: 전력 밀도; 조명 부하 단위: 전력 밀도; 1인당 잠열 취득: 58.6142 W; 1인당 현열 취득: 73.2678 W; 개인별 면적: 28.5714 m2; 실제 전력 부하: 0 W; 실제 조명 부하: 0 W; 지정된 구역별 전력 부하: 13.9931; 지정된 구역별 조명 부하: 10.7639; 지정된 전력 부하: 0 W; 지정된 조명 부하: 0 W; 천장속 조명 방사: 20; 총 개인별 열 취득: 131.882 W
치수 - 계산 높이: 1000 mm; 둘레: 8200 mm; 면적: 4.2 m2; 무한한 높이: 4100 mm; 체적: 17.22 m3

# IfcSpace: 승강기홀 49:5256119, 49
In: 지상 5층
LongName: 승강기홀; InteriorOrExteriorSpace: INTERNAL
Pset_SpaceCommon - Reference: 승강기홀 49; FloorCovering: 쇠흙손마감; WallCovering: 무늬코트뿜칠; CeilingCovering: 지정단열재
BaseQuantities - NetFloorArea: 6.2598 m2; Height: 4100 mm; GrossFloorArea: 6.2598 m2; GrossVolume: 25.6652 m3
ID 데이터 - 바닥 마감: 쇠흙손마감; 번호: 49; 베이스 마감: 목재 걸레받이; 벽 마감: 무늬코트뿜칠; 이름: 승강기홀; 천장 마감: 지정단열재
공정 - 공정: 새 구성
구속조건 - 베이스 간격띄우기: 0 mm; 상한값: 지상 5층; 레벨: 지상 5층; 한계 간격띄우기: 4100 mm
기타 - 거실여부: no; 공정 ID: 0; 카테고리: 룸; 공간분류코드: 33109; 실ID: 517
에너지 해석 - 구역별 실제 전력 부하: 0; 구역별 실제 조명 부하: 0; 기초 전력 부하: 공간 유형별; 기초 조명 부하: 공간 유형별; 사람 수: 0; 열 부하 값: 공간 유형별; 전력 부하 단위: 전력 밀도; 조명 부하 단위: 전력 밀도; 1인당 잠열 취득: 58.6142 W; 1인당 현열 취득: 73.2678 W; 개인별 면적: 28.5714 m2; 실제 전력 부하: 0 W; 실제 조명 부하: 0 W; 지정된 구역별 전력 부하: 13.9931; 지정된 구역별 조명 부하: 10.7639; 지정된 전력 부하: 0 W; 지정된 조명 부하: 0 W; 천장속 조명 방사: 20; 총 개인별 열 취득: 131.882 W
치수 - 계산 높이: 1000 mm; 둘레: 10007.8 mm; 면적: 6.2598 m2; 무한한 높이: 4100 mm; 체적: 25.6637 m3

# IfcSpace: 승강기홀 50:5256122, 50
In: 지상 5층
LongName: 승강기홀; InteriorOrExteriorSpace: INTERNAL
Pset_SpaceCommon - Reference: 승강기홀 50; FloorCovering: 쇠흙손마감; WallCovering: 무늬코트뿜칠; CeilingCovering: 지정단열재
BaseQuantities - NetFloorArea: 8.41095 m2; Height: 4100 mm; GrossFloorArea: 8.41095 m2; GrossVolume: 34.4849 m3
ID 데이터 - 바닥 마감: 쇠흙손마감; 번호: 50; 베이스 마감: 목재 걸레받이; 벽 마감: 무늬코트뿜칠; 이름: 승강기홀; 천장 마감: 지정단열재
공정 - 공정: 새 구성
구속조건 - 베이스 간격띄우기: 0 mm; 상한값: 지상 5층; 레벨: 지상 5층; 한계 간격띄우기: 4100 mm
기타 - 거실여부: no; 공정 ID: 0; 카테고리: 룸; 공간분류코드: 33109; 실ID: 518
에너지 해석 - 구역별 실제 전력 부하: 0; 구역별 실제 조명 부하: 0; 기초 전력 부하: 공간 유형별; 기초 조명 부하: 공간 유형별; 사람 수: 0; 열 부하 값: 공간 유형별; 전력 부하 단위: 전력 밀도; 조명 부하 단위: 전력 밀도; 1인당 잠열 취득: 58.6142 W; 1인당 현열 취득: 73.2678 W; 개인별 면적: 28.5714 m2; 실제 전력 부하: 0 W; 실제 조명 부하: 0 W; 지정된 구역별 전력 부하: 13.9931; 지정된 구역별 조명 부하: 10.7639; 지정된 전력 부하: 0 W; 지정된 조명 부하: 0 W; 천장속 조명 방사: 20; 총 개인별 열 취득: 131.882 W
치수 - 계산 높이: 1000 mm; 둘레: 11607.8 mm; 면적: 8.41095 m2; 무한한 높이: 4100 mm; 체적: 34.4832 m3

# IfcSpace: 승강기홀 51:5256125, 51
In: 지상 5층
LongName: 승강기홀; InteriorOrExteriorSpace: INTERNAL
Pset_SpaceCommon - Reference: 승강기홀 51; FloorCovering: 쇠흙손마감; WallCovering: 무늬코트뿜칠; CeilingCovering: 지정단열재
BaseQuantities - NetFloorArea: 4.2 m2; Height: 4100 mm; GrossPerimeter: 8200 mm; GrossFloorArea: 4.2 m2; GrossVolume: 17.22 m3
ID 데이터 - 바닥 마감: 쇠흙손마감; 번호: 51; 베이스 마감: 목재 걸레받이; 벽 마감: 무늬코트뿜칠; 이름: 승강기홀; 천장 마감: 지정단열재
공정 - 공정: 새 구성
구속조건 - 베이스 간격띄우기: 0 mm; 상한값: 지상 5층; 레벨: 지상 5층; 한계 간격띄우기: 4100 mm
기타 - 거실여부: no; 공정 ID: 0; 카테고리: 룸; 공간분류코드: 33109; 실ID: 519
에너지 해석 - 구역별 실제 전력 부하: 0; 구역별 실제 조명 부하: 0; 기초 전력 부하: 공간 유형별; 기초 조명 부하: 공간 유형별; 사람 수: 0; 열 부하 값: 공간 유형별; 전력 부하 단위: 전력 밀도; 조명 부하 단위: 전력 밀도; 1인당 잠열 취득: 58.6142 W; 1인당 현열 취득: 73.2678 W; 개인별 면적: 28.5714 m2; 실제 전력 부하: 0 W; 실제 조명 부하: 0 W; 지정된 구역별 전력 부하: 13.9931; 지정된 구역별 조명 부하: 10.7639; 지정된 전력 부하: 0 W; 지정된 조명 부하: 0 W; 천장속 조명 방사: 20; 총 개인별 열 취득: 131.882 W
치수 - 계산 높이: 1000 mm; 둘레: 8200 mm; 면적: 4.2 m2; 무한한 높이: 4100 mm; 체적: 17.22 m3

# IfcSpace: 승강기홀 52:5256131, 52
In: 지상 6층
LongName: 승강기홀; InteriorOrExteriorSpace: INTERNAL
Pset_SpaceCommon - Reference: 승강기홀 52; FloorCovering: 쇠흙손마감; WallCovering: 무늬코트뿜칠; CeilingCovering: 지정단열재
BaseQuantities - NetFloorArea: 6.2598 m2; Height: 4100 mm; GrossFloorArea: 6.2598 m2; GrossVolume: 25.6652 m3
ID 데이터 - 바닥 마감: 쇠흙손마감; 번호: 52; 베이스 마감: 목재 걸레받이; 벽 마감: 무늬코트뿜칠; 이름: 승강기홀; 천장 마감: 지정단열재
공정 - 공정: 새 구성
구속조건 - 베이스 간격띄우기: 0 mm; 상한값: 지상 6층; 레벨: 지상 6층; 한계 간격띄우기: 4100 mm
기타 - 거실여부: no; 공정 ID: 0; 카테고리: 룸; 공간분류코드: 33109; 실ID: 614
에너지 해석 - 구역별 실제 전력 부하: 0; 구역별 실제 조명 부하: 0; 기초 전력 부하: 공간 유형별; 기초 조명 부하: 공간 유형별; 사람 수: 0; 열 부하 값: 공간 유형별; 전력 부하 단위: 전력 밀도; 조명 부하 단위: 전력 밀도; 1인당 잠열 취득: 58.6142 W; 1인당 현열 취득: 73.2678 W; 개인별 면적: 28.5714 m2; 실제 전력 부하: 0 W; 실제 조명 부하: 0 W; 지정된 구역별 전력 부하: 13.9931; 지정된 구역별 조명 부하: 10.7639; 지정된 전력 부하: 0 W; 지정된 조명 부하: 0 W; 천장속 조명 방사: 20; 총 개인별 열 취득: 131.882 W
치수 - 계산 높이: 1000 mm; 둘레: 10007.8 mm; 면적: 6.2598 m2; 무한한 높이: 4100 mm; 체적: 25.6637 m3

# IfcSpace: 승강기홀 53:5256134, 53
In: 지상 6층
LongName: 승강기홀; InteriorOrExteriorSpace: INTERNAL
Pset_SpaceCommon - Reference: 승강기홀 53; FloorCovering: 쇠흙손마감; WallCovering: 무늬코트뿜칠; CeilingCovering: 지정단열재
BaseQuantities - NetFloorArea: 8.41095 m2; Height: 4100 mm; GrossFloorArea: 8.41095 m2; GrossVolume: 34.4849 m3
ID 데이터 - 바닥 마감: 쇠흙손마감; 번호: 53; 베이스 마감: 목재 걸레받이; 벽 마감: 무늬코트뿜칠; 이름: 승강기홀; 천장 마감: 지정단열재
공정 - 공정: 새 구성
구속조건 - 베이스 간격띄우기: 0 mm; 상한값: 지상 6층; 레벨: 지상 6층; 한계 간격띄우기: 4100 mm
기타 - 거실여부: no; 공정 ID: 0; 카테고리: 룸; 공간분류코드: 33109; 실ID: 615
에너지 해석 - 구역별 실제 전력 부하: 0; 구역별 실제 조명 부하: 0; 기초 전력 부하: 공간 유형별; 기초 조명 부하: 공간 유형별; 사람 수: 0; 열 부하 값: 공간 유형별; 전력 부하 단위: 전력 밀도; 조명 부하 단위: 전력 밀도; 1인당 잠열 취득: 58.6142 W; 1인당 현열 취득: 73.2678 W; 개인별 면적: 28.5714 m2; 실제 전력 부하: 0 W; 실제 조명 부하: 0 W; 지정된 구역별 전력 부하: 13.9931; 지정된 구역별 조명 부하: 10.7639; 지정된 전력 부하: 0 W; 지정된 조명 부하: 0 W; 천장속 조명 방사: 20; 총 개인별 열 취득: 131.882 W
치수 - 계산 높이: 1000 mm; 둘레: 11607.8 mm; 면적: 8.41095 m2; 무한한 높이: 4100 mm; 체적: 34.4832 m3

# IfcSpace: 승강기홀 54:5256137, 54
In: 지상 6층
LongName: 승강기홀; InteriorOrExteriorSpace: INTERNAL
Pset_SpaceCommon - Reference: 승강기홀 54; FloorCovering: 쇠흙손마감; WallCovering: 무늬코트뿜칠; CeilingCovering: 지정단열재
BaseQuantities - NetFloorArea: 4.2 m2; Height: 4100 mm; GrossPerimeter: 8200 mm; GrossFloorArea: 4.2 m2; GrossVolume: 17.22 m3
ID 데이터 - 바닥 마감: 쇠흙손마감; 번호: 54; 베이스 마감: 목재 걸레받이; 벽 마감: 무늬코트뿜칠; 이름: 승강기홀; 천장 마감: 지정단열재
공정 - 공정: 새 구성
구속조건 - 베이스 간격띄우기: 0 mm; 상한값: 지상 6층; 레벨: 지상 6층; 한계 간격띄우기: 4100 mm
기타 - 거실여부: no; 공정 ID: 0; 카테고리: 룸; 공간분류코드: 33109; 실ID: 616
에너지 해석 - 구역별 실제 전력 부하: 0; 구역별 실제 조명 부하: 0; 기초 전력 부하: 공간 유형별; 기초 조명 부하: 공간 유형별; 사람 수: 0; 열 부하 값: 공간 유형별; 전력 부하 단위: 전력 밀도; 조명 부하 단위: 전력 밀도; 1인당 잠열 취득: 58.6142 W; 1인당 현열 취득: 73.2678 W; 개인별 면적: 28.5714 m2; 실제 전력 부하: 0 W; 실제 조명 부하: 0 W; 지정된 구역별 전력 부하: 13.9931; 지정된 구역별 조명 부하: 10.7639; 지정된 전력 부하: 0 W; 지정된 조명 부하: 0 W; 천장속 조명 방사: 20; 총 개인별 열 취득: 131.882 W
치수 - 계산 높이: 1000 mm; 둘레: 8200 mm; 면적: 4.2 m2; 무한한 높이: 4100 mm; 체적: 17.22 m3

# IfcSpace: 승강기홀 61:5256185, 61
In: 지상 7층
LongName: 승강기홀; InteriorOrExteriorSpace: INTERNAL
Pset_SpaceCommon - Reference: 승강기홀 61; FloorCovering: 쇠흙손마감; WallCovering: 무늬코트뿜칠; CeilingCovering: 지정단열재
BaseQuantities - NetFloorArea: 6.2598 m2; Height: 4100 mm; GrossFloorArea: 6.2598 m2; GrossVolume: 25.6652 m3
ID 데이터 - 바닥 마감: 쇠흙손마감; 번호: 61; 베이스 마감: 목재 걸레받이; 벽 마감: 무늬코트뿜칠; 이름: 승강기홀; 천장 마감: 지정단열재
공정 - 공정: 새 구성
구속조건 - 베이스 간격띄우기: 0 mm; 상한값: 지상 7층; 레벨: 지상 7층; 한계 간격띄우기: 4100 mm
기타 - 거실여부: no; 공정 ID: 0; 카테고리: 룸; 공간분류코드: 33109; 실ID: 717
에너지 해석 - 구역별 실제 전력 부하: 0; 구역별 실제 조명 부하: 0; 기초 전력 부하: 공간 유형별; 기초 조명 부하: 공간 유형별; 사람 수: 0; 열 부하 값: 공간 유형별; 전력 부하 단위: 전력 밀도; 조명 부하 단위: 전력 밀도; 1인당 잠열 취득: 58.6142 W; 1인당 현열 취득: 73.2678 W; 개인별 면적: 28.5714 m2; 실제 전력 부하: 0 W; 실제 조명 부하: 0 W; 지정된 구역별 전력 부하: 13.9931; 지정된 구역별 조명 부하: 10.7639; 지정된 전력 부하: 0 W; 지정된 조명 부하: 0 W; 천장속 조명 방사: 20; 총 개인별 열 취득: 131.882 W
치수 - 계산 높이: 1000 mm; 둘레: 10007.8 mm; 면적: 6.2598 m2; 무한한 높이: 4100 mm; 체적: 25.6637 m3

# IfcSpace: 승강기홀 62:5256188, 62
In: 지상 7층
LongName: 승강기홀; InteriorOrExteriorSpace: INTERNAL
Pset_SpaceCommon - Reference: 승강기홀 62; FloorCovering: 쇠흙손마감; WallCovering: 무늬코트뿜칠; CeilingCovering: 지정단열재
BaseQuantities - NetFloorArea: 8.41095 m2; Height: 4100 mm; GrossFloorArea: 8.41095 m2; GrossVolume: 34.4849 m3
ID 데이터 - 바닥 마감: 쇠흙손마감; 번호: 62; 베이스 마감: 목재 걸레받이; 벽 마감: 무늬코트뿜칠; 이름: 승강기홀; 천장 마감: 지정단열재
공정 - 공정: 새 구성
구속조건 - 베이스 간격띄우기: 0 mm; 상한값: 지상 7층; 레벨: 지상 7층; 한계 간격띄우기: 4100 mm
기타 - 거실여부: no; 공정 ID: 0; 카테고리: 룸; 공간분류코드: 33109; 실ID: 718
에너지 해석 - 구역별 실제 전력 부하: 0; 구역별 실제 조명 부하: 0; 기초 전력 부하: 공간 유형별; 기초 조명 부하: 공간 유형별; 사람 수: 0; 열 부하 값: 공간 유형별; 전력 부하 단위: 전력 밀도; 조명 부하 단위: 전력 밀도; 1인당 잠열 취득: 58.6142 W; 1인당 현열 취득: 73.2678 W; 개인별 면적: 28.5714 m2; 실제 전력 부하: 0 W; 실제 조명 부하: 0 W; 지정된 구역별 전력 부하: 13.9931; 지정된 구역별 조명 부하: 10.7639; 지정된 전력 부하: 0 W; 지정된 조명 부하: 0 W; 천장속 조명 방사: 20; 총 개인별 열 취득: 131.882 W
치수 - 계산 높이: 1000 mm; 둘레: 11607.8 mm; 면적: 8.41095 m2; 무한한 높이: 4100 mm; 체적: 34.4832 m3

# IfcSpace: 승강기홀 63:5256191, 63
In: 지상 7층
LongName: 승강기홀; InteriorOrExteriorSpace: INTERNAL
Pset_SpaceCommon - Reference: 승강기홀 63; FloorCovering: 쇠흙손마감; WallCovering: 무늬코트뿜칠; CeilingCovering: 지정단열재
BaseQuantities - NetFloorArea: 4.2 m2; Height: 4100 mm; GrossPerimeter: 8200 mm; GrossFloorArea: 4.2 m2; GrossVolume: 17.22 m3
ID 데이터 - 바닥 마감: 쇠흙손마감; 번호: 63; 베이스 마감: 목재 걸레받이; 벽 마감: 무늬코트뿜칠; 이름: 승강기홀; 천장 마감: 지정단열재
공정 - 공정: 새 구성
구속조건 - 베이스 간격띄우기: 0 mm; 상한값: 지상 7층; 레벨: 지상 7층; 한계 간격띄우기: 4100 mm
기타 - 거실여부: no; 공정 ID: 0; 카테고리: 룸; 공간분류코드: 33109; 실ID: 719
에너지 해석 - 구역별 실제 전력 부하: 0; 구역별 실제 조명 부하: 0; 기초 전력 부하: 공간 유형별; 기초 조명 부하: 공간 유형별; 사람 수: 0; 열 부하 값: 공간 유형별; 전력 부하 단위: 전력 밀도; 조명 부하 단위: 전력 밀도; 1인당 잠열 취득: 58.6142 W; 1인당 현열 취득: 73.2678 W; 개인별 면적: 28.5714 m2; 실제 전력 부하: 0 W; 실제 조명 부하: 0 W; 지정된 구역별 전력 부하: 13.9931; 지정된 구역별 조명 부하: 10.7639; 지정된 전력 부하: 0 W; 지정된 조명 부하: 0 W; 천장속 조명 방사: 20; 총 개인별 열 취득: 131.882 W
치수 - 계산 높이: 1000 mm; 둘레: 8200 mm; 면적: 4.2 m2; 무한한 높이: 4100 mm; 체적: 17.22 m3

# IfcSpace: 승강기홀 64:5256203, 64
In: 지상 8층
LongName: 승강기홀; InteriorOrExteriorSpace: INTERNAL
Pset_SpaceCommon - Reference: 승강기홀 64; FloorCovering: 쇠흙손마감; WallCovering: 무늬코트뿜칠; CeilingCovering: 지정단열재
BaseQuantities - NetFloorArea: 6.2598 m2; Height: 4100 mm; GrossFloorArea: 6.2598 m2; GrossVolume: 25.6652 m3
ID 데이터 - 바닥 마감: 쇠흙손마감; 번호: 64; 베이스 마감: 목재 걸레받이; 벽 마감: 무늬코트뿜칠; 이름: 승강기홀; 천장 마감: 지정단열재
공정 - 공정: 새 구성
구속조건 - 베이스 간격띄우기: 0 mm; 상한값: 지상 8층; 레벨: 지상 8층; 한계 간격띄우기: 4100 mm
기타 - 거실여부: no; 공정 ID: 0; 카테고리: 룸; 공간분류코드: 33109; 실ID: 811
에너지 해석 - 구역별 실제 전력 부하: 0; 구역별 실제 조명 부하: 0; 기초 전력 부하: 공간 유형별; 기초 조명 부하: 공간 유형별; 사람 수: 0; 열 부하 값: 공간 유형별; 전력 부하 단위: 전력 밀도; 조명 부하 단위: 전력 밀도; 1인당 잠열 취득: 58.6142 W; 1인당 현열 취득: 73.2678 W; 개인별 면적: 28.5714 m2; 실제 전력 부하: 0 W; 실제 조명 부하: 0 W; 지정된 구역별 전력 부하: 13.9931; 지정된 구역별 조명 부하: 10.7639; 지정된 전력 부하: 0 W; 지정된 조명 부하: 0 W; 천장속 조명 방사: 20; 총 개인별 열 취득: 131.882 W
치수 - 계산 높이: 1000 mm; 둘레: 10007.8 mm; 면적: 6.2598 m2; 무한한 높이: 4100 mm; 체적: 25.6637 m3

# IfcSpace: 승강기홀 65:5256206, 65
In: 지상 8층
LongName: 승강기홀; InteriorOrExteriorSpace: INTERNAL
Pset_SpaceCommon - Reference: 승강기홀 65; FloorCovering: 쇠흙손마감; WallCovering: 무늬코트뿜칠; CeilingCovering: 지정단열재
BaseQuantities - NetFloorArea: 8.41095 m2; Height: 4100 mm; GrossFloorArea: 8.41095 m2; GrossVolume: 34.4849 m3
ID 데이터 - 바닥 마감: 쇠흙손마감; 번호: 65; 베이스 마감: 목재 걸레받이; 벽 마감: 무늬코트뿜칠; 이름: 승강기홀; 천장 마감: 지정단열재
공정 - 공정: 새 구성
구속조건 - 베이스 간격띄우기: 0 mm; 상한값: 지상 8층; 레벨: 지상 8층; 한계 간격띄우기: 4100 mm
기타 - 거실여부: no; 공정 ID: 0; 카테고리: 룸; 공간분류코드: 33109; 실ID: 812
에너지 해석 - 구역별 실제 전력 부하: 0; 구역별 실제 조명 부하: 0; 기초 전력 부하: 공간 유형별; 기초 조명 부하: 공간 유형별; 사람 수: 0; 열 부하 값: 공간 유형별; 전력 부하 단위: 전력 밀도; 조명 부하 단위: 전력 밀도; 1인당 잠열 취득: 58.6142 W; 1인당 현열 취득: 73.2678 W; 개인별 면적: 28.5714 m2; 실제 전력 부하: 0 W; 실제 조명 부하: 0 W; 지정된 구역별 전력 부하: 13.9931; 지정된 구역별 조명 부하: 10.7639; 지정된 전력 부하: 0 W; 지정된 조명 부하: 0 W; 천장속 조명 방사: 20; 총 개인별 열 취득: 131.882 W
치수 - 계산 높이: 1000 mm; 둘레: 11607.8 mm; 면적: 8.41095 m2; 무한한 높이: 4100 mm; 체적: 34.4832 m3

# IfcSpace: 승강기홀 66:5256209, 66
In: 지상 8층
LongName: 승강기홀; InteriorOrExteriorSpace: INTERNAL
Pset_SpaceCommon - Reference: 승강기홀 66; FloorCovering: 쇠흙손마감; WallCovering: 무늬코트뿜칠; CeilingCovering: 지정단열재
BaseQuantities - NetFloorArea: 4.2 m2; Height: 4100 mm; GrossPerimeter: 8200 mm; GrossFloorArea: 4.2 m2; GrossVolume: 17.22 m3
ID 데이터 - 바닥 마감: 쇠흙손마감; 번호: 66; 베이스 마감: 목재 걸레받이; 벽 마감: 무늬코트뿜칠; 이름: 승강기홀; 천장 마감: 지정단열재
공정 - 공정: 새 구성
구속조건 - 베이스 간격띄우기: 0 mm; 상한값: 지상 8층; 레벨: 지상 8층; 한계 간격띄우기: 4100 mm
기타 - 거실여부: no; 공정 ID: 0; 카테고리: 룸; 공간분류코드: 33109; 실ID: 813
에너지 해석 - 구역별 실제 전력 부하: 0; 구역별 실제 조명 부하: 0; 기초 전력 부하: 공간 유형별; 기초 조명 부하: 공간 유형별; 사람 수: 0; 열 부하 값: 공간 유형별; 전력 부하 단위: 전력 밀도; 조명 부하 단위: 전력 밀도; 1인당 잠열 취득: 58.6142 W; 1인당 현열 취득: 73.2678 W; 개인별 면적: 28.5714 m2; 실제 전력 부하: 0 W; 실제 조명 부하: 0 W; 지정된 구역별 전력 부하: 13.9931; 지정된 구역별 조명 부하: 10.7639; 지정된 전력 부하: 0 W; 지정된 조명 부하: 0 W; 천장속 조명 방사: 20; 총 개인별 열 취득: 131.882 W
치수 - 계산 높이: 1000 mm; 둘레: 8200 mm; 면적: 4.2 m2; 무한한 높이: 4100 mm; 체적: 17.22 m3

# IfcSpace: 승강기홀 73:5256286, 73
In: 지상 9층
LongName: 승강기홀; InteriorOrExteriorSpace: INTERNAL
Pset_SpaceCommon - Reference: 승강기홀 73; FloorCovering: 쇠흙손마감; WallCovering: 무늬코트뿜칠; CeilingCovering: 지정단열재
BaseQuantities - NetFloorArea: 6.2598 m2; Height: 4500 mm; GrossFloorArea: 6.2598 m2; GrossVolume: 28.1691 m3
ID 데이터 - 바닥 마감: 쇠흙손마감; 번호: 73; 베이스 마감: 목재 걸레받이; 벽 마감: 무늬코트뿜칠; 이름: 승강기홀; 천장 마감: 지정단열재
공정 - 공정: 새 구성
구속조건 - 베이스 간격띄우기: 0 mm; 상한값: 지상 9층; 레벨: 지상 9층; 한계 간격띄우기: 4500 mm
기타 - 거실여부: no; 공정 ID: 0; 카테고리: 룸; 공간분류코드: 33109; 실ID: 913
에너지 해석 - 구역별 실제 전력 부하: 0; 구역별 실제 조명 부하: 0; 기초 전력 부하: 공간 유형별; 기초 조명 부하: 공간 유형별; 사람 수: 0; 열 부하 값: 공간 유형별; 전력 부하 단위: 전력 밀도; 조명 부하 단위: 전력 밀도; 1인당 잠열 취득: 58.6142 W; 1인당 현열 취득: 73.2678 W; 개인별 면적: 28.5714 m2; 실제 전력 부하: 0 W; 실제 조명 부하: 0 W; 지정된 구역별 전력 부하: 13.9931; 지정된 구역별 조명 부하: 10.7639; 지정된 전력 부하: 0 W; 지정된 조명 부하: 0 W; 천장속 조명 방사: 20; 총 개인별 열 취득: 131.882 W
치수 - 계산 높이: 1000 mm; 둘레: 10007.8 mm; 면적: 6.2598 m2; 무한한 높이: 4500 mm; 체적: 28.1676 m3

# IfcSpace: 승강기홀 74:5256289, 74
In: 지상 9층
LongName: 승강기홀; InteriorOrExteriorSpace: INTERNAL
Pset_SpaceCommon - Reference: 승강기홀 74; FloorCovering: 쇠흙손마감; WallCovering: 무늬코트뿜칠; CeilingCovering: 지정단열재
BaseQuantities - NetFloorArea: 8.41095 m2; Height: 4500 mm; GrossFloorArea: 8.41095 m2; GrossVolume: 37.8493 m3
ID 데이터 - 바닥 마감: 쇠흙손마감; 번호: 74; 베이스 마감: 목재 걸레받이; 벽 마감: 무늬코트뿜칠; 이름: 승강기홀; 천장 마감: 지정단열재
공정 - 공정: 새 구성
구속조건 - 베이스 간격띄우기: 0 mm; 상한값: 지상 9층; 레벨: 지상 9층; 한계 간격띄우기: 4500 mm
기타 - 거실여부: no; 공정 ID: 0; 카테고리: 룸; 공간분류코드: 33109; 실ID: 914
에너지 해석 - 구역별 실제 전력 부하: 0; 구역별 실제 조명 부하: 0; 기초 전력 부하: 공간 유형별; 기초 조명 부하: 공간 유형별; 사람 수: 0; 열 부하 값: 공간 유형별; 전력 부하 단위: 전력 밀도; 조명 부하 단위: 전력 밀도; 1인당 잠열 취득: 58.6142 W; 1인당 현열 취득: 73.2678 W; 개인별 면적: 28.5714 m2; 실제 전력 부하: 0 W; 실제 조명 부하: 0 W; 지정된 구역별 전력 부하: 13.9931; 지정된 구역별 조명 부하: 10.7639; 지정된 전력 부하: 0 W; 지정된 조명 부하: 0 W; 천장속 조명 방사: 20; 총 개인별 열 취득: 131.882 W
치수 - 계산 높이: 1000 mm; 둘레: 11607.8 mm; 면적: 8.41095 m2; 무한한 높이: 4500 mm; 체적: 37.8476 m3

# IfcSpace: 승강기홀 75:5256292, 75
In: 지상 9층
LongName: 승강기홀; InteriorOrExteriorSpace: INTERNAL
Pset_SpaceCommon - Reference: 승강기홀 75; FloorCovering: 쇠흙손마감; WallCovering: 무늬코트뿜칠; CeilingCovering: 지정단열재
BaseQuantities - NetFloorArea: 4.2 m2; Height: 4500 mm; GrossPerimeter: 8200 mm; GrossFloorArea: 4.2 m2; GrossVolume: 18.9 m3
ID 데이터 - 바닥 마감: 쇠흙손마감; 번호: 75; 베이스 마감: 목재 걸레받이; 벽 마감: 무늬코트뿜칠; 이름: 승강기홀; 천장 마감: 지정단열재
공정 - 공정: 새 구성
구속조건 - 베이스 간격띄우기: 0 mm; 상한값: 지상 9층; 레벨: 지상 9층; 한계 간격띄우기: 4500 mm
기타 - 거실여부: no; 공정 ID: 0; 카테고리: 룸; 공간분류코드: 33109; 실ID: 915
에너지 해석 - 구역별 실제 전력 부하: 0; 구역별 실제 조명 부하: 0; 기초 전력 부하: 공간 유형별; 기초 조명 부하: 공간 유형별; 사람 수: 0; 열 부하 값: 공간 유형별; 전력 부하 단위: 전력 밀도; 조명 부하 단위: 전력 밀도; 1인당 잠열 취득: 58.6142 W; 1인당 현열 취득: 73.2678 W; 개인별 면적: 28.5714 m2; 실제 전력 부하: 0 W; 실제 조명 부하: 0 W; 지정된 구역별 전력 부하: 13.9931; 지정된 구역별 조명 부하: 10.7639; 지정된 전력 부하: 0 W; 지정된 조명 부하: 0 W; 천장속 조명 방사: 20; 총 개인별 열 취득: 131.882 W
치수 - 계산 높이: 1000 mm; 둘레: 8200 mm; 면적: 4.2 m2; 무한한 높이: 4500 mm; 체적: 18.9 m3

# IfcSpace: 승강기홀 76:5256307, 76
In: 지상 10층
LongName: 승강기홀; InteriorOrExteriorSpace: INTERNAL
Pset_SpaceCommon - Reference: 승강기홀 76; FloorCovering: 쇠흙손마감; WallCovering: 무늬코트뿜칠; CeilingCovering: 지정단열재
BaseQuantities - NetFloorArea: 6.12291 m2; Height: 5000 mm; GrossPerimeter: 9897.84 mm; GrossFloorArea: 6.12291 m2; GrossVolume: 30.6145 m3
ID 데이터 - 바닥 마감: 쇠흙손마감; 번호: 76; 베이스 마감: 목재 걸레받이; 벽 마감: 무늬코트뿜칠; 이름: 승강기홀; 천장 마감: 지정단열재
공정 - 공정: 새 구성
구속조건 - 베이스 간격띄우기: 0 mm; 상한값: 지상 10층; 레벨: 지상 10층; 한계 간격띄우기: 5000 mm
기타 - 거실여부: no; 공정 ID: 0; 카테고리: 룸; 공간분류코드: 33109; 실ID: 1010
에너지 해석 - 구역별 실제 전력 부하: 0; 구역별 실제 조명 부하: 0; 기초 전력 부하: 공간 유형별; 기초 조명 부하: 공간 유형별; 사람 수: 0; 열 부하 값: 공간 유형별; 전력 부하 단위: 전력 밀도; 조명 부하 단위: 전력 밀도; 1인당 잠열 취득: 58.6142 W; 1인당 현열 취득: 73.2678 W; 개인별 면적: 28.5714 m2; 실제 전력 부하: 0 W; 실제 조명 부하: 0 W; 지정된 구역별 전력 부하: 13.9931; 지정된 구역별 조명 부하: 10.7639; 지정된 전력 부하: 0 W; 지정된 조명 부하: 0 W; 천장속 조명 방사: 20; 총 개인별 열 취득: 131.882 W
치수 - 계산 높이: 1000 mm; 둘레: 9897.84 mm; 면적: 6.12291 m2; 무한한 높이: 5000 mm; 체적: 30.6145 m3

# IfcSpace: 승강기홀 77:5256310, 77
In: 지상 10층
LongName: 승강기홀; InteriorOrExteriorSpace: INTERNAL
Pset_SpaceCommon - Reference: 승강기홀 77; FloorCovering: 쇠흙손마감; WallCovering: 무늬코트뿜칠; CeilingCovering: 지정단열재
BaseQuantities - NetFloorArea: 8.00957 m2; Height: 5000 mm; GrossPerimeter: 11327.8 mm; GrossFloorArea: 8.00957 m2; GrossVolume: 40.0479 m3
ID 데이터 - 바닥 마감: 쇠흙손마감; 번호: 77; 베이스 마감: 목재 걸레받이; 벽 마감: 무늬코트뿜칠; 이름: 승강기홀; 천장 마감: 지정단열재
공정 - 공정: 새 구성
구속조건 - 베이스 간격띄우기: 0 mm; 상한값: 지상 10층; 레벨: 지상 10층; 한계 간격띄우기: 5000 mm
기타 - 거실여부: no; 공정 ID: 0; 카테고리: 룸; 공간분류코드: 33109; 실ID: 1011
에너지 해석 - 구역별 실제 전력 부하: 0; 구역별 실제 조명 부하: 0; 기초 전력 부하: 공간 유형별; 기초 조명 부하: 공간 유형별; 사람 수: 0; 열 부하 값: 공간 유형별; 전력 부하 단위: 전력 밀도; 조명 부하 단위: 전력 밀도; 1인당 잠열 취득: 58.6142 W; 1인당 현열 취득: 73.2678 W; 개인별 면적: 28.5714 m2; 실제 전력 부하: 0 W; 실제 조명 부하: 0 W; 지정된 구역별 전력 부하: 13.9931; 지정된 구역별 조명 부하: 10.7639; 지정된 전력 부하: 0 W; 지정된 조명 부하: 0 W; 천장속 조명 방사: 20; 총 개인별 열 취득: 131.882 W
치수 - 계산 높이: 1000 mm; 둘레: 11327.8 mm; 면적: 8.00957 m2; 무한한 높이: 5000 mm; 체적: 40.0479 m3

# IfcSpace: 승강기홀 78:5256313, 78
In: 지상 10층
LongName: 승강기홀; InteriorOrExteriorSpace: INTERNAL
Pset_SpaceCommon - Reference: 승강기홀 78; FloorCovering: 쇠흙손마감; WallCovering: 무늬코트뿜칠; CeilingCovering: 지정단열재
BaseQuantities - NetFloorArea: 4.08708 m2; Height: 5000 mm; GrossPerimeter: 8090 mm; GrossFloorArea: 4.08708 m2; GrossVolume: 20.4354 m3
ID 데이터 - 바닥 마감: 쇠흙손마감; 번호: 78; 베이스 마감: 목재 걸레받이; 벽 마감: 무늬코트뿜칠; 이름: 승강기홀; 천장 마감: 지정단열재
공정 - 공정: 새 구성
구속조건 - 베이스 간격띄우기: 0 mm; 상한값: 지상 10층; 레벨: 지상 10층; 한계 간격띄우기: 5000 mm
기타 - 거실여부: no; 공정 ID: 0; 카테고리: 룸; 공간분류코드: 33109; 실ID: 1012
에너지 해석 - 구역별 실제 전력 부하: 0; 구역별 실제 조명 부하: 0; 기초 전력 부하: 공간 유형별; 기초 조명 부하: 공간 유형별; 사람 수: 0; 열 부하 값: 공간 유형별; 전력 부하 단위: 전력 밀도; 조명 부하 단위: 전력 밀도; 1인당 잠열 취득: 58.6142 W; 1인당 현열 취득: 73.2678 W; 개인별 면적: 28.5714 m2; 실제 전력 부하: 0 W; 실제 조명 부하: 0 W; 지정된 구역별 전력 부하: 13.9931; 지정된 구역별 조명 부하: 10.7639; 지정된 전력 부하: 0 W; 지정된 조명 부하: 0 W; 천장속 조명 방사: 20; 총 개인별 열 취득: 131.882 W
치수 - 계산 높이: 1000 mm; 둘레: 8090 mm; 면적: 4.08708 m2; 무한한 높이: 5000 mm; 체적: 19.8224 m3

# IfcSpace: 승강기홀 8:5255676, 8
In: 지하2층
LongName: 승강기홀; InteriorOrExteriorSpace: INTERNAL
Pset_SpaceCommon - Reference: 승강기홀 8; FloorCovering: 쇠흙손마감; WallCovering: 수성페인트; CeilingCovering: 지정단열재
BaseQuantities - NetFloorArea: 6.25462 m2; Height: 5800 mm; GrossPerimeter: 10003.7 mm; GrossFloorArea: 6.25462 m2; GrossVolume: 36.2768 m3
ID 데이터 - 바닥 마감: 쇠흙손마감; 번호: 8; 베이스 마감: 목재 걸레받이; 벽 마감: 수성페인트; 이름: 승강기홀; 천장 마감: 지정단열재
공정 - 공정: 새 구성
구속조건 - 상한값: 지하2층; 레벨: 지하2층; 베이스 간격띄우기: -1800 mm; 한계 간격띄우기: 4000 mm
기타 - 거실여부: no; 공정 ID: 0; 카테고리: 룸; 공간분류코드: 33109; 실ID: B212
에너지 해석 - 구역별 실제 전력 부하: 0; 구역별 실제 조명 부하: 0; 기초 전력 부하: 공간 유형별; 기초 조명 부하: 공간 유형별; 사람 수: 0; 열 부하 값: 공간 유형별; 전력 부하 단위: 전력 밀도; 조명 부하 단위: 전력 밀도; 1인당 잠열 취득: 58.6142 W; 1인당 현열 취득: 73.2678 W; 개인별 면적: 28.5714 m2; 실제 전력 부하: 0 W; 실제 조명 부하: 0 W; 지정된 구역별 전력 부하: 13.9931; 지정된 구역별 조명 부하: 10.7639; 지정된 전력 부하: 0 W; 지정된 조명 부하: 0 W; 천장속 조명 방사: 20; 총 개인별 열 취득: 131.882 W
치수 - 계산 높이: 0 mm; 둘레: 10003.7 mm; 면적: 6.25462 m2; 무한한 높이: 5800 mm; 체적: 36.2768 m3

# IfcSpace: 승강기홀 9:5255679, 9
In: 지하2층
LongName: 승강기홀; InteriorOrExteriorSpace: INTERNAL
Pset_SpaceCommon - Reference: 승강기홀 9; FloorCovering: 쇠흙손마감; WallCovering: 수성페인트; CeilingCovering: 지정단열재
BaseQuantities - NetFloorArea: 8.4 m2; Height: 4000 mm; GrossPerimeter: 11600 mm; GrossFloorArea: 8.4 m2; GrossVolume: 33.6 m3
ID 데이터 - 바닥 마감: 쇠흙손마감; 번호: 9; 베이스 마감: 목재 걸레받이; 벽 마감: 수성페인트; 이름: 승강기홀; 천장 마감: 지정단열재
공정 - 공정: 새 구성
구속조건 - 베이스 간격띄우기: 0 mm; 상한값: 지하2층; 레벨: 지하2층; 한계 간격띄우기: 4000 mm
기타 - 거실여부: no; 공정 ID: 0; 카테고리: 룸; 공간분류코드: 33109; 실ID: B213
에너지 해석 - 구역별 실제 전력 부하: 0; 구역별 실제 조명 부하: 0; 기초 전력 부하: 공간 유형별; 기초 조명 부하: 공간 유형별; 사람 수: 0; 열 부하 값: 공간 유형별; 전력 부하 단위: 전력 밀도; 조명 부하 단위: 전력 밀도; 1인당 잠열 취득: 58.6142 W; 1인당 현열 취득: 73.2678 W; 개인별 면적: 28.5714 m2; 실제 전력 부하: 0 W; 실제 조명 부하: 0 W; 지정된 구역별 전력 부하: 13.9931; 지정된 구역별 조명 부하: 10.7639; 지정된 전력 부하: 0 W; 지정된 조명 부하: 0 W; 천장속 조명 방사: 20; 총 개인별 열 취득: 131.882 W
치수 - 계산 높이: 0 mm; 둘레: 11600 mm; 면적: 8.4 m2; 무한한 높이: 4000 mm; 체적: 33.6 m3

# IfcSpace: 옥탑1층 8:3580439, 8
In: 옥탑층
LongName: 옥탑1층; InteriorOrExteriorSpace: INTERNAL; Group: Rentable
Pset_SpaceCommon - Reference: 옥탑1층 8
BaseQuantities - NetFloorArea: 96.436 m2; Height: 1 mm; GrossFloorArea: 96.436 m2; GrossVolume: 0.096436 m3
ID 데이터 - 번호: 8; 이름: 옥탑1층; 해설: BIM 산출
구속조건 - 레벨: 지붕층
기타 - 면적 양식 ID: 482395; 카테고리: 면적; 면적 유형: 바닥 면적
치수 - 계산 높이: 1000 mm; 둘레: 47681.5 mm; 면적: 96.436 m2

# IfcSpace: 저수조실 128:3690412, 128
In: 지하2층
LongName: 저수조실; InteriorOrExteriorSpace: INTERNAL
Pset_SpaceCommon - Reference: 저수조실 128; FloorCovering: -; WallCovering: -; CeilingCovering: 수성페인트 2회
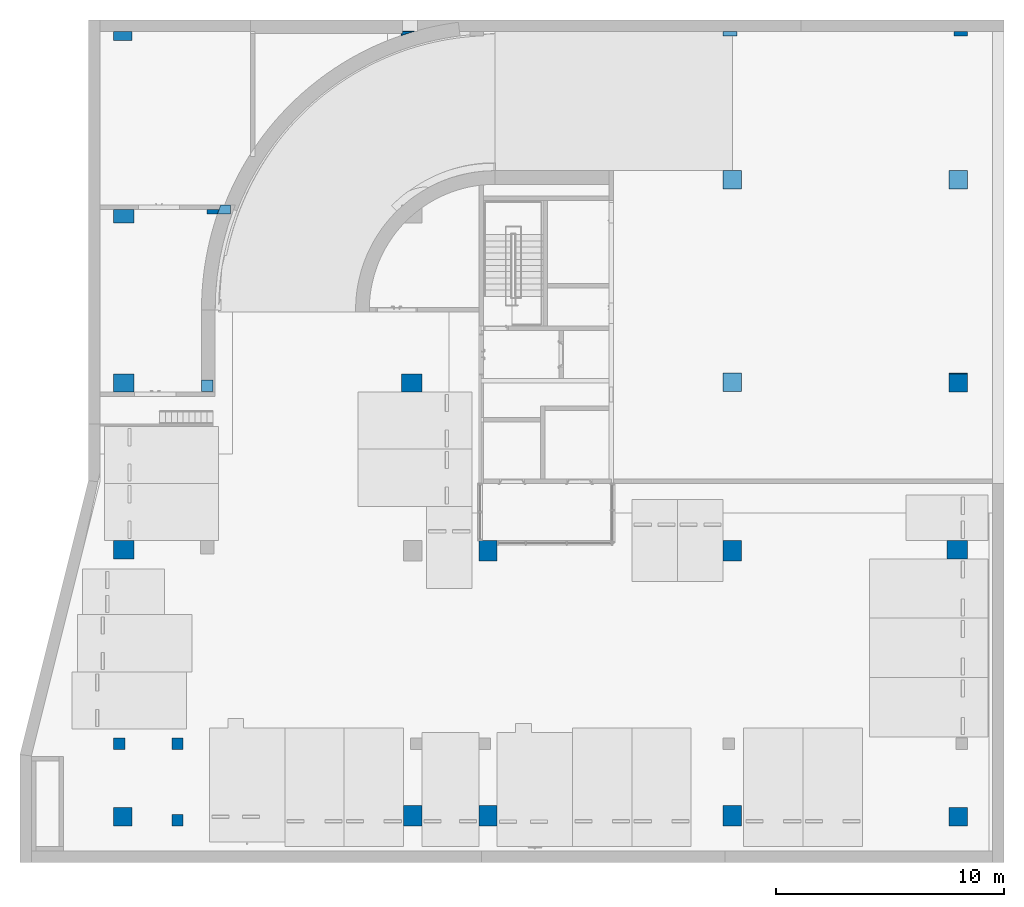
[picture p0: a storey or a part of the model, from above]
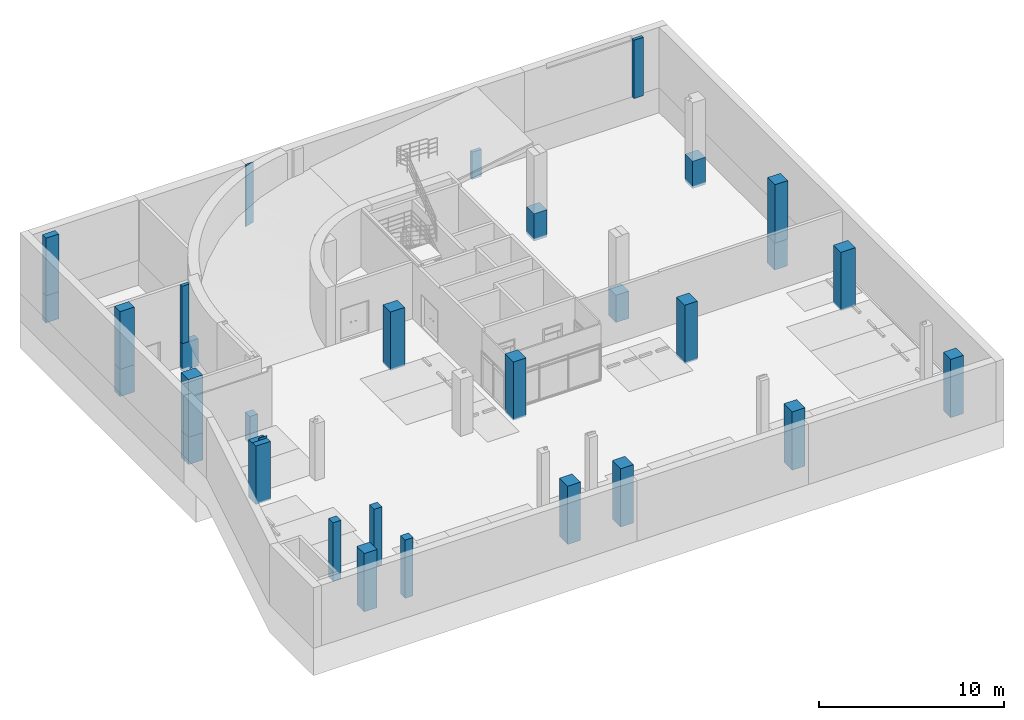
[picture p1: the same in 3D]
Properties of the parts of a building model (IFC2X3), part 5 of 39

# IfcSpace: 저수조실 128:3690412, 128
BaseQuantities - NetFloorArea: 48.4606 m2; Height: 5650 mm; GrossFloorArea: 48.4606 m2; GrossVolume: 273.802 m3
ID 데이터 - 바닥 마감: -; 번호: 128; 베이스 마감: 목재 걸레받이; 벽 마감: -; 이름: 저수조실; 천장 마감: 수성페인트 2회
공정 - 공정: 새 구성
구속조건 - 상한값: 지하2층; 레벨: 지하2층; 베이스 간격띄우기: -1800 mm; 한계 간격띄우기: 3850 mm
기타 - 거실여부: no; 공정 ID: 0; 카테고리: 룸; 공간분류코드: 33415; 실ID: B204
에너지 해석 - 구역별 실제 전력 부하: 0; 구역별 실제 조명 부하: 0; 기초 전력 부하: 공간 유형별; 기초 조명 부하: 공간 유형별; 사람 수: 0; 열 부하 값: 공간 유형별; 전력 부하 단위: 전력 밀도; 조명 부하 단위: 전력 밀도; 1인당 잠열 취득: 58.6142 W; 1인당 현열 취득: 73.2678 W; 개인별 면적: 28.5714 m2; 실제 전력 부하: 0 W; 실제 조명 부하: 0 W; 지정된 구역별 전력 부하: 13.9931; 지정된 구역별 조명 부하: 10.7639; 지정된 전력 부하: 0 W; 지정된 조명 부하: 0 W; 천장속 조명 방사: 20; 총 개인별 열 취득: 131.882 W
치수 - 계산 높이: 0 mm; 둘레: 28286.4 mm; 면적: 48.4606 m2; 무한한 높이: 5650 mm; 체적: 271.379 m3

# IfcSpace: 전기실/발전기실 144:3691177, 144
In: 지하1층
LongName: 전기실/발전기실; InteriorOrExteriorSpace: INTERNAL
Pset_SpaceCommon - Reference: 전기실/발전기실 144; FloorCovering: 우레탄페인트; WallCovering: -; CeilingCovering: 수성페인트 2회
BaseQuantities - NetFloorArea: 33.0129 m2; Height: 5900 mm; GrossPerimeter: 26353 mm; GrossFloorArea: 33.0129 m2; GrossVolume: 194.776 m3
ID 데이터 - 바닥 마감: 우레탄페인트; 번호: 144; 베이스 마감: 목재 걸레받이; 벽 마감: -; 이름: 전기실/발전기실; 천장 마감: 수성페인트 2회
공정 - 공정: 새 구성
구속조건 - 베이스 간격띄우기: 0 mm; 상한값: 지하1층; 레벨: 지하1층; 한계 간격띄우기: 5900 mm
기타 - 거실여부: no; 공정 ID: 0; 카테고리: 룸; 공간분류코드: 33408; 실ID: B107
에너지 해석 - 구역별 실제 전력 부하: 0; 구역별 실제 조명 부하: 0; 기초 전력 부하: 공간 유형별; 기초 조명 부하: 공간 유형별; 사람 수: 0; 열 부하 값: 공간 유형별; 전력 부하 단위: 전력 밀도; 조명 부하 단위: 전력 밀도; 1인당 잠열 취득: 58.6142 W; 1인당 현열 취득: 73.2678 W; 개인별 면적: 28.5714 m2; 실제 전력 부하: 0 W; 실제 조명 부하: 0 W; 지정된 구역별 전력 부하: 13.9931; 지정된 구역별 조명 부하: 10.7639; 지정된 전력 부하: 0 W; 지정된 조명 부하: 0 W; 천장속 조명 방사: 20; 총 개인별 열 취득: 131.882 W
치수 - 계산 높이: 0 mm; 둘레: 26202 mm; 면적: 33.0129 m2; 무한한 높이: 5900 mm; 체적: 194.776 m3

# IfcSpace: 전기실/발전기실 145:3691180, 145
In: 지하1층
LongName: 전기실/발전기실; InteriorOrExteriorSpace: INTERNAL
Pset_SpaceCommon - Reference: 전기실/발전기실 145; FloorCovering: 우레탄페인트; WallCovering: -; CeilingCovering: 수성페인트 2회
BaseQuantities - NetFloorArea: 38.5298 m2; Height: 5900 mm; GrossPerimeter: 25564.1 mm; GrossFloorArea: 38.5298 m2; GrossVolume: 227.326 m3
ID 데이터 - 바닥 마감: 우레탄페인트; 번호: 145; 베이스 마감: 목재 걸레받이; 벽 마감: -; 이름: 전기실/발전기실; 천장 마감: 수성페인트 2회
공정 - 공정: 새 구성
구속조건 - 베이스 간격띄우기: 0 mm; 상한값: 지하1층; 레벨: 지하1층; 한계 간격띄우기: 5900 mm
기타 - 거실여부: no; 공정 ID: 0; 카테고리: 룸; 공간분류코드: 33408; 실ID: B108
에너지 해석 - 구역별 실제 전력 부하: 0; 구역별 실제 조명 부하: 0; 기초 전력 부하: 공간 유형별; 기초 조명 부하: 공간 유형별; 사람 수: 0; 열 부하 값: 공간 유형별; 전력 부하 단위: 전력 밀도; 조명 부하 단위: 전력 밀도; 1인당 잠열 취득: 58.6142 W; 1인당 현열 취득: 73.2678 W; 개인별 면적: 28.5714 m2; 실제 전력 부하: 0 W; 실제 조명 부하: 0 W; 지정된 구역별 전력 부하: 13.9931; 지정된 구역별 조명 부하: 10.7639; 지정된 전력 부하: 0 W; 지정된 조명 부하: 0 W; 천장속 조명 방사: 20; 총 개인별 열 취득: 131.882 W
치수 - 계산 높이: 0 mm; 둘레: 25556.4 mm; 면적: 38.5298 m2; 무한한 높이: 5900 mm; 체적: 227.326 m3

# IfcSpace: 전실 133:3690448, 133
In: 지하2층
LongName: 전실; InteriorOrExteriorSpace: INTERNAL
Pset_SpaceCommon - Reference: 전실 133; FloorCovering: T30 화강석 물갈기; WallCovering: T30화강석물갈기; CeilingCovering: 무늬코트뿜칠
BaseQuantities - NetFloorArea: 6.93388 m2; Height: 3850 mm; GrossPerimeter: 10803.7 mm; GrossFloorArea: 6.93388 m2; GrossVolume: 26.6954 m3
ID 데이터 - 바닥 마감: T30 화강석 물갈기; 번호: 133; 베이스 마감: 목재 걸레받이; 벽 마감: T30화강석물갈기; 이름: 전실; 천장 마감: 무늬코트뿜칠
공정 - 공정: 새 구성
구속조건 - 베이스 간격띄우기: 0 mm; 상한값: 지하2층; 레벨: 지하2층; 한계 간격띄우기: 3850 mm
기타 - 거실여부: no; 공정 ID: 0; 카테고리: 룸; 공간분류코드: 33114; 실ID: B209
에너지 해석 - 구역별 실제 전력 부하: 0; 구역별 실제 조명 부하: 0; 기초 전력 부하: 공간 유형별; 기초 조명 부하: 공간 유형별; 사람 수: 0; 열 부하 값: 공간 유형별; 전력 부하 단위: 전력 밀도; 조명 부하 단위: 전력 밀도; 1인당 잠열 취득: 58.6142 W; 1인당 현열 취득: 73.2678 W; 개인별 면적: 28.5714 m2; 실제 전력 부하: 0 W; 실제 조명 부하: 0 W; 지정된 구역별 전력 부하: 13.9931; 지정된 구역별 조명 부하: 10.7639; 지정된 전력 부하: 0 W; 지정된 조명 부하: 0 W; 천장속 조명 방사: 20; 총 개인별 열 취득: 131.882 W
치수 - 계산 높이: 0 mm; 둘레: 10803.7 mm; 면적: 6.93388 m2; 무한한 높이: 3850 mm; 체적: 26.6954 m3

# IfcSpace: 전실 140:3691075, 140
In: 지하1층
LongName: 전실; InteriorOrExteriorSpace: INTERNAL
Pset_SpaceCommon - Reference: 전실 140; FloorCovering: T30 화강석 물갈기; WallCovering: T30화강석물갈기; CeilingCovering: 무늬코트뿜칠
BaseQuantities - NetFloorArea: 6.93388 m2; Height: 5950 mm; GrossPerimeter: 10803.7 mm; GrossFloorArea: 6.93388 m2; GrossVolume: 41.2566 m3
ID 데이터 - 바닥 마감: T30 화강석 물갈기; 번호: 140; 베이스 마감: 목재 걸레받이; 벽 마감: T30화강석물갈기; 이름: 전실; 천장 마감: 무늬코트뿜칠
공정 - 공정: 새 구성
구속조건 - 베이스 간격띄우기: 0 mm; 레벨: 지하1층; 상한값: 지상 1층; 한계 간격띄우기: -150 mm
기타 - 거실여부: no; 공정 ID: 0; 카테고리: 룸; 공간분류코드: 33114; 실ID: B104
에너지 해석 - 구역별 실제 전력 부하: 0; 구역별 실제 조명 부하: 0; 기초 전력 부하: 공간 유형별; 기초 조명 부하: 공간 유형별; 사람 수: 0; 열 부하 값: 공간 유형별; 전력 부하 단위: 전력 밀도; 조명 부하 단위: 전력 밀도; 1인당 잠열 취득: 58.6142 W; 1인당 현열 취득: 73.2678 W; 개인별 면적: 28.5714 m2; 실제 전력 부하: 0 W; 실제 조명 부하: 0 W; 지정된 구역별 전력 부하: 13.9931; 지정된 구역별 조명 부하: 10.7639; 지정된 전력 부하: 0 W; 지정된 조명 부하: 0 W; 천장속 조명 방사: 20; 총 개인별 열 취득: 131.882 W
치수 - 계산 높이: 0 mm; 둘레: 10803.7 mm; 면적: 6.93388 m2; 무한한 높이: 5950 mm; 체적: 41.2566 m3

# IfcSpace: 전실 169:3691280, 169
In: 지상 1층
LongName: 전실; InteriorOrExteriorSpace: INTERNAL
Pset_SpaceCommon - Reference: 전실 169; FloorCovering: T30 화강석 물갈기; WallCovering: T30화강석물갈기; CeilingCovering: T12암면흡음택스마감/T9.5일반석고보드
BaseQuantities - NetFloorArea: 6.77786 m2; Height: 3580 mm; GrossPerimeter: 10695.7 mm; GrossFloorArea: 6.77786 m2; GrossVolume: 24.2647 m3
ID 데이터 - 바닥 마감: T30 화강석 물갈기; 번호: 169; 베이스 마감: 목재 걸레받이; 벽 마감: T30화강석물갈기; 이름: 전실; 천장 마감: T12암면흡음택스마감/T9.5일반석고보드
공정 - 공정: 새 구성
구속조건 - 베이스 간격띄우기: 0 mm; 상한값: 지상 1층; 레벨: 지상 1층; 한계 간격띄우기: 3580 mm
기타 - 거실여부: no; 공정 ID: 0; 카테고리: 룸; 방화구획: yes; 공간분류코드: 33114; 실ID: 120
에너지 해석 - 구역별 실제 전력 부하: 0; 구역별 실제 조명 부하: 0; 기초 전력 부하: 공간 유형별; 기초 조명 부하: 공간 유형별; 사람 수: 0; 열 부하 값: 공간 유형별; 전력 부하 단위: 전력 밀도; 조명 부하 단위: 전력 밀도; 1인당 잠열 취득: 58.6142 W; 1인당 현열 취득: 73.2678 W; 개인별 면적: 28.5714 m2; 실제 전력 부하: 0 W; 실제 조명 부하: 0 W; 지정된 구역별 전력 부하: 13.9931; 지정된 구역별 조명 부하: 10.7639; 지정된 전력 부하: 0 W; 지정된 조명 부하: 0 W; 천장속 조명 방사: 20; 총 개인별 열 취득: 131.882 W
치수 - 계산 높이: 1000 mm; 둘레: 10695.7 mm; 면적: 6.77786 m2; 무한한 높이: 3580 mm; 체적: 24.2647 m3

# IfcSpace: 전실 185:3691540, 185
In: 지상 2층
LongName: 전실; InteriorOrExteriorSpace: INTERNAL
Pset_SpaceCommon - Reference: 전실 185; FloorCovering: T30 화강석 물갈기; WallCovering: T30화강석물갈기; CeilingCovering: T12암면흡음택스마감/T9.5일반석고보드
BaseQuantities - NetFloorArea: 6.73691 m2; Height: 3180 mm; GrossPerimeter: 10656 mm; GrossFloorArea: 6.73691 m2; GrossVolume: 21.4234 m3
ID 데이터 - 바닥 마감: T30 화강석 물갈기; 번호: 185; 베이스 마감: 목재 걸레받이; 벽 마감: T30화강석물갈기; 이름: 전실; 천장 마감: T12암면흡음택스마감/T9.5일반석고보드
공정 - 공정: 새 구성
구속조건 - 베이스 간격띄우기: 0 mm; 상한값: 지상 2층; 레벨: 지상 2층; 한계 간격띄우기: 3180 mm
기타 - 거실여부: no; 공정 ID: 0; 카테고리: 룸; 방화구획: yes; 공간분류코드: 33114; 실ID: 207
에너지 해석 - 구역별 실제 전력 부하: 0; 구역별 실제 조명 부하: 0; 기초 전력 부하: 공간 유형별; 기초 조명 부하: 공간 유형별; 사람 수: 0; 열 부하 값: 공간 유형별; 전력 부하 단위: 전력 밀도; 조명 부하 단위: 전력 밀도; 1인당 잠열 취득: 58.6142 W; 1인당 현열 취득: 73.2678 W; 개인별 면적: 28.5714 m2; 실제 전력 부하: 0 W; 실제 조명 부하: 0 W; 지정된 구역별 전력 부하: 13.9931; 지정된 구역별 조명 부하: 10.7639; 지정된 전력 부하: 0 W; 지정된 조명 부하: 0 W; 천장속 조명 방사: 20; 총 개인별 열 취득: 131.882 W
치수 - 계산 높이: 1000 mm; 둘레: 10656 mm; 면적: 6.73691 m2; 무한한 높이: 3180 mm; 체적: 21.4234 m3

# IfcSpace: 전실 201:3691783, 201
In: 지상 3층
LongName: 전실; InteriorOrExteriorSpace: INTERNAL
Pset_SpaceCommon - Reference: 전실 201; FloorCovering: T30 화강석 물갈기; WallCovering: T30화강석물갈기; CeilingCovering: T12암면흡음택스마감/T9.5일반석고보드
BaseQuantities - NetFloorArea: 6.73691 m2; Height: 2980 mm; GrossPerimeter: 10656 mm; GrossFloorArea: 6.73691 m2; GrossVolume: 20.076 m3
ID 데이터 - 바닥 마감: T30 화강석 물갈기; 번호: 201; 베이스 마감: 목재 걸레받이; 벽 마감: T30화강석물갈기; 이름: 전실; 천장 마감: T12암면흡음택스마감/T9.5일반석고보드
공정 - 공정: 새 구성
구속조건 - 베이스 간격띄우기: 0 mm; 상한값: 지상 3층; 레벨: 지상 3층; 한계 간격띄우기: 2980 mm
기타 - 거실여부: no; 공정 ID: 0; 카테고리: 룸; 방화구획: yes; 공간분류코드: 33114; 실ID: 310
에너지 해석 - 구역별 실제 전력 부하: 0; 구역별 실제 조명 부하: 0; 기초 전력 부하: 공간 유형별; 기초 조명 부하: 공간 유형별; 사람 수: 0; 열 부하 값: 공간 유형별; 전력 부하 단위: 전력 밀도; 조명 부하 단위: 전력 밀도; 1인당 잠열 취득: 58.6142 W; 1인당 현열 취득: 73.2678 W; 개인별 면적: 28.5714 m2; 실제 전력 부하: 0 W; 실제 조명 부하: 0 W; 지정된 구역별 전력 부하: 13.9931; 지정된 구역별 조명 부하: 10.7639; 지정된 전력 부하: 0 W; 지정된 조명 부하: 0 W; 천장속 조명 방사: 20; 총 개인별 열 취득: 131.882 W
치수 - 계산 높이: 1000 mm; 둘레: 10656 mm; 면적: 6.73691 m2; 무한한 높이: 2980 mm; 체적: 20.076 m3

# IfcSpace: 전실 223:3692906, 223
In: 지상 4층
LongName: 전실; InteriorOrExteriorSpace: INTERNAL
Pset_SpaceCommon - Reference: 전실 223; FloorCovering: T30 화강석 물갈기; WallCovering: T30화강석물갈기; CeilingCovering: T12암면흡음택스마감/T9.5일반석고보드
BaseQuantities - NetFloorArea: 6.73822 m2; Height: 2980 mm; GrossPerimeter: 10657.3 mm; GrossFloorArea: 6.73822 m2; GrossVolume: 20.0799 m3
ID 데이터 - 바닥 마감: T30 화강석 물갈기; 번호: 223; 베이스 마감: 목재 걸레받이; 벽 마감: T30화강석물갈기; 이름: 전실; 천장 마감: T12암면흡음택스마감/T9.5일반석고보드
공정 - 공정: 새 구성
구속조건 - 베이스 간격띄우기: 0 mm; 상한값: 지상 4층; 레벨: 지상 4층; 한계 간격띄우기: 2980 mm
기타 - 거실여부: no; 공정 ID: 0; 카테고리: 룸; 방화구획: yes; 공간분류코드: 33114; 실ID: 412
에너지 해석 - 구역별 실제 전력 부하: 0; 구역별 실제 조명 부하: 0; 기초 전력 부하: 공간 유형별; 기초 조명 부하: 공간 유형별; 사람 수: 0; 열 부하 값: 공간 유형별; 전력 부하 단위: 전력 밀도; 조명 부하 단위: 전력 밀도; 1인당 잠열 취득: 58.6142 W; 1인당 현열 취득: 73.2678 W; 개인별 면적: 28.5714 m2; 실제 전력 부하: 0 W; 실제 조명 부하: 0 W; 지정된 구역별 전력 부하: 13.9931; 지정된 구역별 조명 부하: 10.7639; 지정된 전력 부하: 0 W; 지정된 조명 부하: 0 W; 천장속 조명 방사: 20; 총 개인별 열 취득: 131.882 W
치수 - 계산 높이: 1000 mm; 둘레: 10657.3 mm; 면적: 6.73822 m2; 무한한 높이: 2980 mm; 체적: 20.0799 m3

# IfcSpace: 전실 224:3692912, 224
In: 지상 5층
LongName: 전실; InteriorOrExteriorSpace: INTERNAL
Pset_SpaceCommon - Reference: 전실 224; FloorCovering: T30 화강석 물갈기; WallCovering: T30화강석물갈기; CeilingCovering: T12암면흡음택스마감/T9.5일반석고보드
BaseQuantities - NetFloorArea: 6.73822 m2; Height: 2980 mm; GrossPerimeter: 10657.3 mm; GrossFloorArea: 6.73822 m2; GrossVolume: 20.0799 m3
ID 데이터 - 바닥 마감: T30 화강석 물갈기; 번호: 224; 베이스 마감: 목재 걸레받이; 벽 마감: T30화강석물갈기; 이름: 전실; 천장 마감: T12암면흡음택스마감/T9.5일반석고보드
공정 - 공정: 새 구성
구속조건 - 베이스 간격띄우기: 0 mm; 레벨: 지상 5층; 상한값: 지상 5층; 한계 간격띄우기: 2980 mm
기타 - 거실여부: no; 공정 ID: 0; 카테고리: 룸; 방화구획: yes; 공간분류코드: 33114; 실ID: 501
에너지 해석 - 구역별 실제 전력 부하: 0; 구역별 실제 조명 부하: 0; 기초 전력 부하: 공간 유형별; 기초 조명 부하: 공간 유형별; 사람 수: 0; 열 부하 값: 공간 유형별; 전력 부하 단위: 전력 밀도; 조명 부하 단위: 전력 밀도; 1인당 잠열 취득: 58.6142 W; 1인당 현열 취득: 73.2678 W; 개인별 면적: 28.5714 m2; 실제 전력 부하: 0 W; 실제 조명 부하: 0 W; 지정된 구역별 전력 부하: 13.9931; 지정된 구역별 조명 부하: 10.7639; 지정된 전력 부하: 0 W; 지정된 조명 부하: 0 W; 천장속 조명 방사: 20; 총 개인별 열 취득: 131.882 W
치수 - 계산 높이: 1000 mm; 둘레: 10657.3 mm; 면적: 6.73822 m2; 무한한 높이: 2980 mm; 체적: 20.0799 m3

# IfcSpace: 전실 239:3694121, 239
In: 지상 6층
LongName: 전실; InteriorOrExteriorSpace: INTERNAL
Pset_SpaceCommon - Reference: 전실 239; FloorCovering: T30 화강석 물갈기; WallCovering: T30화강석물갈기; CeilingCovering: T12암면흡음택스마감/T9.5일반석고보드
BaseQuantities - NetFloorArea: 6.73691 m2; Height: 2980 mm; GrossPerimeter: 10656 mm; GrossFloorArea: 6.73691 m2; GrossVolume: 20.076 m3
ID 데이터 - 바닥 마감: T30 화강석 물갈기; 번호: 239; 베이스 마감: 목재 걸레받이; 벽 마감: T30화강석물갈기; 이름: 전실; 천장 마감: T12암면흡음택스마감/T9.5일반석고보드
공정 - 공정: 새 구성
구속조건 - 베이스 간격띄우기: 0 mm; 레벨: 지상 6층; 상한값: 지상 6층; 한계 간격띄우기: 2980 mm
기타 - 거실여부: no; 공정 ID: 0; 카테고리: 룸; 방화구획: yes; 공간분류코드: 33114; 실ID: 601
에너지 해석 - 구역별 실제 전력 부하: 0; 구역별 실제 조명 부하: 0; 기초 전력 부하: 공간 유형별; 기초 조명 부하: 공간 유형별; 사람 수: 0; 열 부하 값: 공간 유형별; 전력 부하 단위: 전력 밀도; 조명 부하 단위: 전력 밀도; 1인당 잠열 취득: 58.6142 W; 1인당 현열 취득: 73.2678 W; 개인별 면적: 28.5714 m2; 실제 전력 부하: 0 W; 실제 조명 부하: 0 W; 지정된 구역별 전력 부하: 13.9931; 지정된 구역별 조명 부하: 10.7639; 지정된 전력 부하: 0 W; 지정된 조명 부하: 0 W; 천장속 조명 방사: 20; 총 개인별 열 취득: 131.882 W
치수 - 계산 높이: 1000 mm; 둘레: 10656 mm; 면적: 6.73691 m2; 무한한 높이: 2980 mm; 체적: 20.076 m3

# IfcSpace: 전실 265:3694355, 265
In: 지상 7층
LongName: 전실; InteriorOrExteriorSpace: INTERNAL
Pset_SpaceCommon - Reference: 전실 265; FloorCovering: T30 화강석 물갈기; WallCovering: T30화강석물갈기; CeilingCovering: T12암면흡음택스마감/T9.5일반석고보드
BaseQuantities - NetFloorArea: 6.73691 m2; Height: 2980 mm; GrossPerimeter: 10656 mm; GrossFloorArea: 6.73691 m2; GrossVolume: 20.076 m3
ID 데이터 - 바닥 마감: T30 화강석 물갈기; 번호: 265; 베이스 마감: 목재 걸레받이; 벽 마감: T30화강석물갈기; 이름: 전실; 천장 마감: T12암면흡음택스마감/T9.5일반석고보드
공정 - 공정: 새 구성
구속조건 - 베이스 간격띄우기: 0 mm; 상한값: 지상 7층; 레벨: 지상 7층; 한계 간격띄우기: 2980 mm
기타 - 거실여부: no; 공정 ID: 0; 카테고리: 룸; 방화구획: yes; 공간분류코드: 33114; 실ID: 710
에너지 해석 - 구역별 실제 전력 부하: 0; 구역별 실제 조명 부하: 0; 기초 전력 부하: 공간 유형별; 기초 조명 부하: 공간 유형별; 사람 수: 0; 열 부하 값: 공간 유형별; 전력 부하 단위: 전력 밀도; 조명 부하 단위: 전력 밀도; 1인당 잠열 취득: 58.6142 W; 1인당 현열 취득: 73.2678 W; 개인별 면적: 28.5714 m2; 실제 전력 부하: 0 W; 실제 조명 부하: 0 W; 지정된 구역별 전력 부하: 13.9931; 지정된 구역별 조명 부하: 10.7639; 지정된 전력 부하: 0 W; 지정된 조명 부하: 0 W; 천장속 조명 방사: 20; 총 개인별 열 취득: 131.882 W
치수 - 계산 높이: 1000 mm; 둘레: 10656 mm; 면적: 6.73691 m2; 무한한 높이: 2980 mm; 체적: 20.076 m3

# IfcSpace: 전실 280:3694569, 280
In: 지상 8층
LongName: 전실; InteriorOrExteriorSpace: INTERNAL
Pset_SpaceCommon - Reference: 전실 280; FloorCovering: T30 화강석 물갈기; WallCovering: T30화강석물갈기; CeilingCovering: T12암면흡음택스마감/T9.5일반석고보드
BaseQuantities - NetFloorArea: 6.73691 m2; Height: 2980 mm; GrossPerimeter: 10656 mm; GrossFloorArea: 6.73691 m2; GrossVolume: 20.076 m3
ID 데이터 - 바닥 마감: T30 화강석 물갈기; 번호: 280; 베이스 마감: 목재 걸레받이; 벽 마감: T30화강석물갈기; 이름: 전실; 천장 마감: T12암면흡음택스마감/T9.5일반석고보드
공정 - 공정: 새 구성
구속조건 - 베이스 간격띄우기: 0 mm; 상한값: 지상 8층; 레벨: 지상 8층; 한계 간격띄우기: 2980 mm
기타 - 거실여부: no; 공정 ID: 0; 카테고리: 룸; 공간분류코드: 33114; 실ID: 807
에너지 해석 - 구역별 실제 전력 부하: 0; 구역별 실제 조명 부하: 0; 기초 전력 부하: 공간 유형별; 기초 조명 부하: 공간 유형별; 사람 수: 0; 열 부하 값: 공간 유형별; 전력 부하 단위: 전력 밀도; 조명 부하 단위: 전력 밀도; 1인당 잠열 취득: 58.6142 W; 1인당 현열 취득: 73.2678 W; 개인별 면적: 28.5714 m2; 실제 전력 부하: 0 W; 실제 조명 부하: 0 W; 지정된 구역별 전력 부하: 13.9931; 지정된 구역별 조명 부하: 10.7639; 지정된 전력 부하: 0 W; 지정된 조명 부하: 0 W; 천장속 조명 방사: 20; 총 개인별 열 취득: 131.882 W
치수 - 계산 높이: 1000 mm; 둘레: 10656 mm; 면적: 6.73691 m2; 무한한 높이: 2980 mm; 체적: 20.076 m3

# IfcSpace: 전실 293:3694735, 293
In: 지상 9층
LongName: 전실; InteriorOrExteriorSpace: INTERNAL
Pset_SpaceCommon - Reference: 전실 293; FloorCovering: T30 화강석 물갈기; WallCovering: T30화강석물갈기; CeilingCovering: T12암면흡음택스마감/T9.5일반석고보드
BaseQuantities - NetFloorArea: 6.73691 m2; Height: 3080 mm; GrossPerimeter: 10656 mm; GrossFloorArea: 6.73691 m2; GrossVolume: 20.7497 m3
ID 데이터 - 바닥 마감: T30 화강석 물갈기; 번호: 293; 베이스 마감: 목재 걸레받이; 벽 마감: T30화강석물갈기; 이름: 전실; 천장 마감: T12암면흡음택스마감/T9.5일반석고보드
공정 - 공정: 새 구성
구속조건 - 베이스 간격띄우기: 0 mm; 상한값: 지상 9층; 레벨: 지상 9층; 한계 간격띄우기: 3080 mm
기타 - 거실여부: no; 공정 ID: 0; 카테고리: 룸; 공간분류코드: 33114; 실ID: 904
에너지 해석 - 구역별 실제 전력 부하: 0; 구역별 실제 조명 부하: 0; 기초 전력 부하: 공간 유형별; 기초 조명 부하: 공간 유형별; 사람 수: 0; 열 부하 값: 공간 유형별; 전력 부하 단위: 전력 밀도; 조명 부하 단위: 전력 밀도; 1인당 잠열 취득: 58.6142 W; 1인당 현열 취득: 73.2678 W; 개인별 면적: 28.5714 m2; 실제 전력 부하: 0 W; 실제 조명 부하: 0 W; 지정된 구역별 전력 부하: 13.9931; 지정된 구역별 조명 부하: 10.7639; 지정된 전력 부하: 0 W; 지정된 조명 부하: 0 W; 천장속 조명 방사: 20; 총 개인별 열 취득: 131.882 W
치수 - 계산 높이: 1000 mm; 둘레: 10656 mm; 면적: 6.73691 m2; 무한한 높이: 3080 mm; 체적: 20.7497 m3

# IfcSpace: 전실 311:3694931, 311
In: 지상 10층
LongName: 전실; InteriorOrExteriorSpace: INTERNAL
Pset_SpaceCommon - Reference: 전실 311; FloorCovering: T30 화강석 물갈기; WallCovering: T30화강석물갈기; CeilingCovering: T12암면흡음택스마감/T9.5일반석고보드
BaseQuantities - NetFloorArea: 6.75703 m2; Height: 3580 mm; GrossFloorArea: 6.75703 m2; GrossVolume: 24.1902 m3
ID 데이터 - 바닥 마감: T30 화강석 물갈기; 번호: 311; 베이스 마감: 목재 걸레받이; 벽 마감: T30화강석물갈기; 이름: 전실; 천장 마감: T12암면흡음택스마감/T9.5일반석고보드
공정 - 공정: 새 구성
구속조건 - 베이스 간격띄우기: 0 mm; 상한값: 지상 10층; 레벨: 지상 10층; 한계 간격띄우기: 3580 mm
기타 - 거실여부: no; 공정 ID: 0; 카테고리: 룸; 공간분류코드: 33114; 실ID: 1007
에너지 해석 - 구역별 실제 전력 부하: 0; 구역별 실제 조명 부하: 0; 기초 전력 부하: 공간 유형별; 기초 조명 부하: 공간 유형별; 사람 수: 0; 열 부하 값: 공간 유형별; 전력 부하 단위: 전력 밀도; 조명 부하 단위: 전력 밀도; 1인당 잠열 취득: 58.6142 W; 1인당 현열 취득: 73.2678 W; 개인별 면적: 28.5714 m2; 실제 전력 부하: 0 W; 실제 조명 부하: 0 W; 지정된 구역별 전력 부하: 13.9931; 지정된 구역별 조명 부하: 10.7639; 지정된 전력 부하: 0 W; 지정된 조명 부하: 0 W; 천장속 조명 방사: 20; 총 개인별 열 취득: 131.882 W
치수 - 계산 높이: 1000 mm; 둘레: 10656 mm; 면적: 6.75703 m2; 무한한 높이: 3580 mm; 체적: 23.6496 m3

# IfcSpace: 전실 323:3695673, 323
In: 옥탑층
LongName: 전실; InteriorOrExteriorSpace: INTERNAL
Pset_SpaceCommon - Reference: 전실 323; FloorCovering: T30 화강석 물갈기; WallCovering: T30화강석물갈기; CeilingCovering: T12암면흡음택스마감/T9.5일반석고보드
BaseQuantities - NetFloorArea: 6.93388 m2; Height: 2680 mm; GrossPerimeter: 10803.7 mm; GrossFloorArea: 6.93388 m2; GrossVolume: 18.5828 m3
ID 데이터 - 바닥 마감: T30 화강석 물갈기; 번호: 323; 베이스 마감: 목재 걸레받이; 벽 마감: T30화강석물갈기; 이름: 전실; 천장 마감: T12암면흡음택스마감/T9.5일반석고보드
공정 - 공정: 새 구성
구속조건 - 베이스 간격띄우기: 0 mm; 상한값: 옥탑층; 레벨: 옥탑층; 한계 간격띄우기: 2680 mm
기타 - 거실여부: no; 공정 ID: 0; 카테고리: 룸; 공간분류코드: 33114; 실ID: RF06
에너지 해석 - 구역별 실제 전력 부하: 0; 구역별 실제 조명 부하: 0; 기초 전력 부하: 공간 유형별; 기초 조명 부하: 공간 유형별; 사람 수: 0; 열 부하 값: 공간 유형별; 전력 부하 단위: 전력 밀도; 조명 부하 단위: 전력 밀도; 1인당 잠열 취득: 58.6142 W; 1인당 현열 취득: 73.2678 W; 개인별 면적: 28.5714 m2; 실제 전력 부하: 0 W; 실제 조명 부하: 0 W; 지정된 구역별 전력 부하: 13.9931; 지정된 구역별 조명 부하: 10.7639; 지정된 전력 부하: 0 W; 지정된 조명 부하: 0 W; 천장속 조명 방사: 20; 총 개인별 열 취득: 131.882 W
치수 - 계산 높이: 0 mm; 둘레: 10803.7 mm; 면적: 6.93388 m2; 무한한 높이: 2680 mm; 체적: 18.5828 m3

# IfcSpace: 종교시설 중 종교집회장 10:7412647, 10
In: 지상 10층
LongName: 종교시설 중 종교집회장; InteriorOrExteriorSpace: INTERNAL; Group: 용도구획
Pset_SpaceCommon - Reference: 종교시설 중 종교집회장 10
BaseQuantities - NetFloorArea: 945.182 m2; Height: 5000 mm; GrossFloorArea: 945.182 m2; GrossVolume: 4725.91 m3
ID 데이터 - 번호: 10; 이름: 종교시설 중 종교집회장
구속조건 - 레벨: 지상 10층
기타 - 카테고리: 면적; 면적 양식 ID: 7408029; 면적 유형: 건물 일반 면적; 용도분류코드: 060100
치수 - 계산 높이: 1000 mm; 둘레: 187675 mm; 면적: 945.182 m2

# IfcSpace: 종교시설 중 종교집회장 20:7412040, 20
In: 지상 3층
LongName: 종교시설 중 종교집회장; InteriorOrExteriorSpace: INTERNAL; Group: 용도구획
Pset_SpaceCommon - Reference: 종교시설 중 종교집회장 20
BaseQuantities - NetFloorArea: 945.182 m2; Height: 4100 mm; GrossFloorArea: 945.182 m2; GrossVolume: 3875.25 m3
ID 데이터 - 번호: 20; 이름: 종교시설 중 종교집회장
구속조건 - 레벨: 지상 3층
기타 - 카테고리: 면적; 면적 양식 ID: 7408029; 면적 유형: 건물 일반 면적
치수 - 계산 높이: 1000 mm; 둘레: 187675 mm; 면적: 945.182 m2

# IfcSpace: 종교시설 중 종교집회장 4:7412122, 4
In: 지상 4층
LongName: 종교시설 중 종교집회장; InteriorOrExteriorSpace: INTERNAL; Group: 용도구획
Pset_SpaceCommon - Reference: 종교시설 중 종교집회장 4
BaseQuantities - NetFloorArea: 945.182 m2; Height: 4100 mm; GrossFloorArea: 945.182 m2; GrossVolume: 3875.25 m3
ID 데이터 - 번호: 4; 이름: 종교시설 중 종교집회장
구속조건 - 레벨: 지상 4층
기타 - 카테고리: 면적; 면적 양식 ID: 7408029; 면적 유형: 건물 일반 면적; 용도분류코드: 060100
치수 - 계산 높이: 1000 mm; 둘레: 187675 mm; 면적: 945.182 m2

# IfcSpace: 종교시설 중 종교집회장 5:7412199, 5
In: 지상 5층
LongName: 종교시설 중 종교집회장; InteriorOrExteriorSpace: INTERNAL; Group: 용도구획
Pset_SpaceCommon - Reference: 종교시설 중 종교집회장 5
BaseQuantities - NetFloorArea: 945.182 m2; Height: 4100 mm; GrossFloorArea: 945.182 m2; GrossVolume: 3875.25 m3
ID 데이터 - 번호: 5; 이름: 종교시설 중 종교집회장
구속조건 - 레벨: 지상 5층
기타 - 카테고리: 면적; 면적 양식 ID: 7408029; 면적 유형: 건물 일반 면적; 용도분류코드: 060100
치수 - 계산 높이: 1000 mm; 둘레: 187675 mm; 면적: 945.182 m2

# IfcSpace: 종교시설 중 종교집회장 6:7412284, 6
In: 지상 6층
LongName: 종교시설 중 종교집회장; InteriorOrExteriorSpace: INTERNAL; Group: 용도구획
Pset_SpaceCommon - Reference: 종교시설 중 종교집회장 6
BaseQuantities - NetFloorArea: 945.182 m2; Height: 4100 mm; GrossFloorArea: 945.182 m2; GrossVolume: 3875.25 m3
ID 데이터 - 번호: 6; 이름: 종교시설 중 종교집회장
구속조건 - 레벨: 지상 6층
기타 - 카테고리: 면적; 면적 양식 ID: 7408029; 면적 유형: 건물 일반 면적; 용도분류코드: 060100
치수 - 계산 높이: 1000 mm; 둘레: 187675 mm; 면적: 945.182 m2

# IfcSpace: 종교시설 중 종교집회장 7:7412382, 7
In: 지상 7층
LongName: 종교시설 중 종교집회장; InteriorOrExteriorSpace: INTERNAL; Group: 용도구획
Pset_SpaceCommon - Reference: 종교시설 중 종교집회장 7
BaseQuantities - NetFloorArea: 945.182 m2; Height: 4100 mm; GrossFloorArea: 945.182 m2; GrossVolume: 3875.25 m3
ID 데이터 - 번호: 7; 이름: 종교시설 중 종교집회장
구속조건 - 레벨: 지상 7층
기타 - 카테고리: 면적; 면적 양식 ID: 7408029; 면적 유형: 건물 일반 면적; 용도분류코드: 060100
치수 - 계산 높이: 1000 mm; 둘레: 187675 mm; 면적: 945.182 m2

# IfcSpace: 종교시설 중 종교집회장 8:7412472, 8
In: 지상 8층
LongName: 종교시설 중 종교집회장; InteriorOrExteriorSpace: INTERNAL; Group: 용도구획
Pset_SpaceCommon - Reference: 종교시설 중 종교집회장 8
BaseQuantities - NetFloorArea: 945.182 m2; Height: 4100 mm; GrossFloorArea: 945.182 m2; GrossVolume: 3875.25 m3
ID 데이터 - 번호: 8; 이름: 종교시설 중 종교집회장
구속조건 - 레벨: 지상 8층
기타 - 카테고리: 면적; 면적 양식 ID: 7408029; 면적 유형: 건물 일반 면적; 용도분류코드: 060100
치수 - 계산 높이: 1000 mm; 둘레: 187675 mm; 면적: 945.182 m2

# IfcSpace: 종교시설 중 종교집회장 9:7412561, 9
In: 지상 9층
LongName: 종교시설 중 종교집회장; InteriorOrExteriorSpace: INTERNAL; Group: 용도구획
Pset_SpaceCommon - Reference: 종교시설 중 종교집회장 9
BaseQuantities - NetFloorArea: 945.182 m2; Height: 4500 mm; GrossFloorArea: 945.182 m2; GrossVolume: 4253.32 m3
ID 데이터 - 번호: 9; 이름: 종교시설 중 종교집회장
구속조건 - 레벨: 지상 9층
기타 - 카테고리: 면적; 면적 양식 ID: 7408029; 면적 유형: 건물 일반 면적; 용도분류코드: 060100
치수 - 계산 높이: 1000 mm; 둘레: 187675 mm; 면적: 945.182 m2

# IfcSpace: 주차램프 101:6519562, 101
In: 지하2층
LongName: 주차램프; InteriorOrExteriorSpace: INTERNAL
Pset_SpaceCommon - Reference: 주차램프 101; FloorCovering: 에폭시페인트; WallCovering: -; CeilingCovering: 수성페인트 2회
BaseQuantities - NetFloorArea: 118.897 m2; Height: 3850 mm; GrossFloorArea: 118.897 m2; GrossVolume: 457.754 m3
ID 데이터 - 바닥 마감: 에폭시페인트; 번호: 101; 베이스 마감: 목재 걸레받이; 벽 마감: -; 이름: 주차램프; 천장 마감: 수성페인트 2회
공정 - 공정: 새 구성
구속조건 - 베이스 간격띄우기: 0 mm; 상한값: 지하2층; 레벨: 지하2층; 한계 간격띄우기: 3850 mm
기타 - 거실여부: no; 공정 ID: 0; 카테고리: 룸; 공간분류코드: 33113; 실ID: B217
에너지 해석 - 구역별 실제 전력 부하: 0; 구역별 실제 조명 부하: 0; 기초 전력 부하: 공간 유형별; 기초 조명 부하: 공간 유형별; 사람 수: 0; 열 부하 값: 공간 유형별; 전력 부하 단위: 전력 밀도; 조명 부하 단위: 전력 밀도; 1인당 잠열 취득: 58.6142 W; 1인당 현열 취득: 73.2678 W; 개인별 면적: 28.5714 m2; 실제 전력 부하: 0 W; 실제 조명 부하: 0 W; 지정된 구역별 전력 부하: 13.9931; 지정된 구역별 조명 부하: 10.7639; 지정된 전력 부하: 0 W; 지정된 조명 부하: 0 W; 천장속 조명 방사: 20; 총 개인별 열 취득: 131.882 W
치수 - 계산 높이: 0 mm; 둘레: 51815.8 mm; 면적: 118.897 m2; 무한한 높이: 3850 mm; 체적: 457.681 m3

# IfcSpace: 주차장 100:6519552, 100
In: 지하1층
LongName: 주차장; InteriorOrExteriorSpace: INTERNAL
Pset_SpaceCommon - Reference: 주차장 100; FloorCovering: 에폭시페인트; WallCovering: -; CeilingCovering: 수성페인트 2회
BaseQuantities - NetFloorArea: 149.615 m2; Height: 5950 mm; GrossFloorArea: 149.615 m2; GrossVolume: 890.208 m3
ID 데이터 - 바닥 마감: 에폭시페인트; 번호: 100; 베이스 마감: 목재 걸레받이; 벽 마감: -; 이름: 주차장; 천장 마감: 수성페인트 2회
공정 - 공정: 새 구성
구속조건 - 베이스 간격띄우기: 0 mm; 상한값: 지상 1층; 레벨: 지하1층; 한계 간격띄우기: -150 mm
기타 - 거실여부: no; 공정 ID: 0; 카테고리: 룸; 공간분류코드: 33113; 실ID: B116
에너지 해석 - 구역별 실제 전력 부하: 0; 구역별 실제 조명 부하: 0; 기초 전력 부하: 공간 유형별; 기초 조명 부하: 공간 유형별; 사람 수: 0; 열 부하 값: 공간 유형별; 전력 부하 단위: 전력 밀도; 조명 부하 단위: 전력 밀도; 1인당 잠열 취득: 58.6142 W; 1인당 현열 취득: 73.2678 W; 개인별 면적: 28.5714 m2; 실제 전력 부하: 0 W; 실제 조명 부하: 0 W; 지정된 구역별 전력 부하: 13.9931; 지정된 구역별 조명 부하: 10.7639; 지정된 전력 부하: 0 W; 지정된 조명 부하: 0 W; 천장속 조명 방사: 20; 총 개인별 열 취득: 131.882 W
치수 - 계산 높이: 0 mm; 둘레: 61567.6 mm; 면적: 149.615 m2; 무한한 높이: 5950 mm; 체적: 859.967 m3

# IfcSpace: 주차장 125:3689680, 125
In: 지하2층
LongName: 주차장; InteriorOrExteriorSpace: INTERNAL
Pset_SpaceCommon - Reference: 주차장 125; FloorCovering: 에폭시페인트; WallCovering: -; CeilingCovering: 수성페인트 2회
BaseQuantities - NetFloorArea: 728.288 m2; Height: 3850 mm; GrossFloorArea: 728.288 m2; GrossVolume: 2803.91 m3
ID 데이터 - 바닥 마감: 에폭시페인트; 번호: 125; 베이스 마감: 목재 걸레받이; 벽 마감: -; 이름: 주차장; 천장 마감: 수성페인트 2회
공정 - 공정: 새 구성
구속조건 - 레벨: 지하2층; 베이스 간격띄우기: 0 mm; 상한값: 지하2층; 한계 간격띄우기: 3850 mm
기타 - 거실여부: no; 공간분류코드: 33113; 공정 ID: 0; 실ID: B201; 카테고리: 룸
에너지 해석 - 1인당 잠열 취득: 58.6142 W; 1인당 현열 취득: 73.2678 W; 개인별 면적: 28.5714 m2; 구역별 실제 전력 부하: 0; 구역별 실제 조명 부하: 0; 기초 전력 부하: 공간 유형별; 기초 조명 부하: 공간 유형별; 사람 수: 0; 실제 전력 부하: 0 W; 실제 조명 부하: 0 W; 열 부하 값: 공간 유형별; 전력 부하 단위: 전력 밀도; 조명 부하 단위: 전력 밀도; 지정된 구역별 전력 부하: 13.9931; 지정된 구역별 조명 부하: 10.7639; 지정된 전력 부하: 0 W; 지정된 조명 부하: 0 W; 천장속 조명 방사: 20; 총 개인별 열 취득: 131.882 W
치수 - 계산 높이: 0 mm; 둘레: 135576 mm; 면적: 728.288 m2; 무한한 높이: 3850 mm; 체적: 2802.61 m3

# IfcSpace: 주차장 136:3690715, 136
In: 지하1층
LongName: 주차장; InteriorOrExteriorSpace: INTERNAL
Pset_SpaceCommon - Reference: 주차장 136; FloorCovering: 에폭시페인트; WallCovering: -; CeilingCovering: 수성페인트 2회
BaseQuantities - NetFloorArea: 1040.05 m2; Height: 2438.4 mm; GrossFloorArea: 1040.05 m2; GrossVolume: 2536.05 m3
ID 데이터 - 바닥 마감: 에폭시페인트; 번호: 136; 베이스 마감: 목재 걸레받이; 벽 마감: -; 이름: 주차장; 천장 마감: 수성페인트 2회
공정 - 공정: 새 구성
구속조건 - 베이스 간격띄우기: 0 mm; 레벨: 지하1층; 상한값: 지하1층; 한계 간격띄우기: 2438.4 mm
기타 - 거실여부: no; 공정 ID: 0; 카테고리: 룸; 공간분류코드: 33113; 실ID: B101
에너지 해석 - 구역별 실제 전력 부하: 0; 구역별 실제 조명 부하: 0; 기초 전력 부하: 공간 유형별; 기초 조명 부하: 공간 유형별; 사람 수: 0; 열 부하 값: 공간 유형별; 전력 부하 단위: 전력 밀도; 조명 부하 단위: 전력 밀도; 1인당 잠열 취득: 58.6142 W; 1인당 현열 취득: 73.2678 W; 개인별 면적: 28.5714 m2; 실제 전력 부하: 0 W; 실제 조명 부하: 0 W; 지정된 구역별 전력 부하: 13.9931; 지정된 구역별 조명 부하: 10.7639; 지정된 전력 부하: 0 W; 지정된 조명 부하: 0 W; 천장속 조명 방사: 20; 총 개인별 열 취득: 131.882 W
치수 - 계산 높이: 0 mm; 둘레: 177376 mm; 면적: 1040.05 m2; 무한한 높이: 2438.4 mm; 체적: 2535.93 m3

# IfcSpace: 지상10층 32:5285531, 32
In: 지상 10층
LongName: 지상10층; InteriorOrExteriorSpace: INTERNAL; Group: Rentable
Pset_SpaceCommon - Reference: 지상10층 32
BaseQuantities - NetFloorArea: 1151.4 m2; Height: 5000 mm; GrossFloorArea: 1151.4 m2; GrossVolume: 5757.02 m3
ID 데이터 - 번호: 32; 이름: 지상10층
구속조건 - 레벨: 지상 10층
기타 - 면적 양식 ID: 482395; 카테고리: 면적; 면적 유형: 건축 면적
치수 - 계산 높이: 1000 mm; 둘레: 149842 mm; 면적: 1151.4 m2

# IfcSpace: 지상1층 6:3579108, 6
In: 지상 1층
LongName: 지상1층; InteriorOrExteriorSpace: INTERNAL; Group: Rentable
Pset_SpaceCommon - Reference: 지상1층 6
BaseQuantities - NetFloorArea: 1152.87 m2; Height: 4800 mm; GrossFloorArea: 1152.87 m2; GrossVolume: 5533.8 m3
ID 데이터 - 번호: 6; 이름: 지상1층; 해설: BIM 산출
구속조건 - 레벨: 지상 1층
기타 - 면적 양식 ID: 482395; 카테고리: 면적; 면적 유형: 바닥 면적
치수 - 계산 높이: 1000 mm; 둘레: 147250 mm; 면적: 1152.87 m2

# IfcSpace: 지상2층 7:3579978, 7
In: 지상 2층
LongName: 지상2층; InteriorOrExteriorSpace: INTERNAL; Group: Rentable
Pset_SpaceCommon - Reference: 지상2층 7
BaseQuantities - NetFloorArea: 1152.85 m2; Height: 4500 mm; GrossFloorArea: 1152.85 m2; GrossVolume: 5187.82 m3
ID 데이터 - 번호: 7; 이름: 지상2층; 해설: BIM 산출
구속조건 - 레벨: 지상 2층
기타 - 면적 양식 ID: 482395; 카테고리: 면적; 면적 유형: 바닥 면적
치수 - 계산 높이: 1000 mm; 둘레: 151850 mm; 면적: 1152.85 m2

# IfcSpace: 지상3층 11:5285323, 11
In: 지상 3층
LongName: 지상3층; InteriorOrExteriorSpace: INTERNAL; Group: Rentable
Pset_SpaceCommon - Reference: 지상3층 11
BaseQuantities - NetFloorArea: 1154.04 m2; Height: 4100 mm; GrossFloorArea: 1154.04 m2; GrossVolume: 4731.55 m3
ID 데이터 - 번호: 11; 이름: 지상3층; 해설: BIM 산출
구속조건 - 레벨: 지상 3층
기타 - 면적 양식 ID: 482395; 카테고리: 면적; 면적 유형: 바닥 면적
치수 - 계산 높이: 1000 mm; 둘레: 149800 mm; 면적: 1154.04 m2

# IfcSpace: 지상4층 26:5285453, 26
In: 지상 4층
LongName: 지상4층; InteriorOrExteriorSpace: INTERNAL; Group: Rentable
Pset_SpaceCommon - Reference: 지상4층 26
BaseQuantities - NetFloorArea: 1151.23 m2; Height: 4100 mm; GrossFloorArea: 1151.23 m2; GrossVolume: 4720.05 m3
ID 데이터 - 번호: 26; 이름: 지상4층
구속조건 - 레벨: 지상 4층
기타 - 면적 양식 ID: 482395; 카테고리: 면적; 면적 유형: 건축 면적
치수 - 계산 높이: 1000 mm; 둘레: 149650 mm; 면적: 1151.23 m2

# IfcSpace: 지상5층 27:5285477, 27
In: 지상 5층
LongName: 지상5층; InteriorOrExteriorSpace: INTERNAL; Group: Rentable
Pset_SpaceCommon - Reference: 지상5층 27
BaseQuantities - NetFloorArea: 1158.84 m2; Height: 4100 mm; GrossFloorArea: 1158.84 m2; GrossVolume: 4751.24 m3
ID 데이터 - 번호: 27; 이름: 지상5층
구속조건 - 레벨: 지상 5층
기타 - 면적 양식 ID: 482395; 카테고리: 면적; 면적 유형: 건축 면적
치수 - 계산 높이: 1000 mm; 둘레: 150101 mm; 면적: 1158.84 m2

# IfcSpace: 지상6층 28:5285490, 28
In: 지상 6층
LongName: 지상6층; InteriorOrExteriorSpace: INTERNAL; Group: Rentable
Pset_SpaceCommon - Reference: 지상6층 28
BaseQuantities - NetFloorArea: 1158.84 m2; Height: 4100 mm; GrossFloorArea: 1158.84 m2; GrossVolume: 4751.24 m3
ID 데이터 - 번호: 28; 이름: 지상6층
구속조건 - 레벨: 지상 6층
기타 - 면적 양식 ID: 482395; 카테고리: 면적; 면적 유형: 건축 면적
치수 - 계산 높이: 1000 mm; 둘레: 150101 mm; 면적: 1158.84 m2

# IfcSpace: 지상7층 29:5285503, 29
In: 지상 7층
LongName: 지상7층; InteriorOrExteriorSpace: INTERNAL; Group: Rentable
Pset_SpaceCommon - Reference: 지상7층 29
BaseQuantities - NetFloorArea: 1158.84 m2; Height: 4100 mm; GrossFloorArea: 1158.84 m2; GrossVolume: 4751.24 m3
ID 데이터 - 번호: 29; 이름: 지상7층
구속조건 - 레벨: 지상 7층
기타 - 면적 양식 ID: 482395; 카테고리: 면적; 면적 유형: 건축 면적
치수 - 계산 높이: 1000 mm; 둘레: 150101 mm; 면적: 1158.84 m2

# IfcSpace: 지상8층 30:5285516, 30
In: 지상 8층
LongName: 지상8층; InteriorOrExteriorSpace: INTERNAL; Group: Rentable
Pset_SpaceCommon - Reference: 지상8층 30
BaseQuantities - NetFloorArea: 1158.84 m2; Height: 4100 mm; GrossFloorArea: 1158.84 m2; GrossVolume: 4751.24 m3
ID 데이터 - 번호: 30; 이름: 지상8층
구속조건 - 레벨: 지상 8층
기타 - 면적 양식 ID: 482395; 카테고리: 면적; 면적 유형: 건축 면적
치수 - 계산 높이: 1000 mm; 둘레: 150101 mm; 면적: 1158.84 m2

# IfcSpace: 지상9층 31:5285529, 31
In: 지상 9층
LongName: 지상9층; InteriorOrExteriorSpace: INTERNAL; Group: Rentable
Pset_SpaceCommon - Reference: 지상9층 31
BaseQuantities - NetFloorArea: 1151.21 m2; Height: 4500 mm; GrossFloorArea: 1151.21 m2; GrossVolume: 5180.44 m3
ID 데이터 - 번호: 31; 이름: 지상9층
구속조건 - 레벨: 지상 9층
기타 - 면적 양식 ID: 482395; 카테고리: 면적; 면적 유형: 건축 면적
치수 - 계산 높이: 1000 mm; 둘레: 149650 mm; 면적: 1151.21 m2

# IfcSpace: 지하1층 2:3576491, 2
In: 지하1층
LongName: 지하1층; InteriorOrExteriorSpace: INTERNAL; Group: Rentable
Pset_SpaceCommon - Reference: 지하1층 2
BaseQuantities - NetFloorArea: 1417.26 m2; Height: 6100 mm; GrossFloorArea: 1417.26 m2; GrossVolume: 8645.3 m3
ID 데이터 - 번호: 2; 이름: 지하1층; 해설: BIM 산출
구속조건 - 레벨: 지하1층
기타 - 면적 양식 ID: 482395; 면적 유형: 바닥 면적; 카테고리: 면적
치수 - 계산 높이: 0 mm; 둘레: 153369 mm; 면적: 1417.26 m2

# IfcSpace: 지하2층 4:3577185, 4
In: 지하2층
LongName: 지하2층; InteriorOrExteriorSpace: INTERNAL; Group: Rentable
Pset_SpaceCommon - Reference: 지하2층 4
BaseQuantities - NetFloorArea: 1392.57 m2; Height: 4000 mm; GrossFloorArea: 1392.57 m2; GrossVolume: 5570.29 m3
ID 데이터 - 번호: 4; 이름: 지하2층; 해설: BIM 산출
구속조건 - 레벨: 지하2층
기타 - 면적 양식 ID: 482395; 카테고리: 면적; 면적 유형: 바닥 면적
치수 - 계산 높이: 0 mm; 둘레: 154326 mm; 면적: 1392.57 m2

# IfcSpace: 판매시설 중 상점 15:7411257, 15
In: 지상 1층
LongName: 판매시설 중 상점; InteriorOrExteriorSpace: INTERNAL; Group: 용도구획
Pset_SpaceCommon - Reference: 판매시설 중 상점 15
BaseQuantities - NetFloorArea: 279.402 m2; Height: 4800 mm; GrossFloorArea: 279.402 m2; GrossVolume: 1341.13 m3
ID 데이터 - 번호: 15; 이름: 판매시설 중 상점
구속조건 - 레벨: 지상 1층
기타 - 카테고리: 면적; 면적 양식 ID: 7408029; 면적 유형: 건물 일반 면적; 용도분류코드: 070200
치수 - 계산 높이: 1000 mm; 둘레: 72200 mm; 면적: 279.402 m2

# IfcSpace: 판매시설 중 상점 16:7411258, 16
In: 지상 1층
LongName: 판매시설 중 상점; InteriorOrExteriorSpace: INTERNAL; Group: 용도구획
Pset_SpaceCommon - Reference: 판매시설 중 상점 16
BaseQuantities - NetFloorArea: 166.17 m2; Height: 4800 mm; GrossFloorArea: 166.17 m2; GrossVolume: 797.617 m3
ID 데이터 - 번호: 16; 이름: 판매시설 중 상점
구속조건 - 레벨: 지상 1층
기타 - 카테고리: 면적; 면적 양식 ID: 7408029; 면적 유형: 건물 일반 면적; 용도분류코드: 070200
치수 - 계산 높이: 1000 mm; 둘레: 51600 mm; 면적: 166.17 m2

# IfcSpace: 판매시설 중 상점 17:7411259, 17
In: 지상 1층
LongName: 판매시설 중 상점; InteriorOrExteriorSpace: INTERNAL; Group: 용도구획
Pset_SpaceCommon - Reference: 판매시설 중 상점 17
BaseQuantities - NetFloorArea: 264.078 m2; Height: 4800 mm; GrossFloorArea: 264.078 m2; GrossVolume: 1267.58 m3
ID 데이터 - 번호: 17; 이름: 판매시설 중 상점
구속조건 - 레벨: 지상 1층
기타 - 카테고리: 면적; 면적 양식 ID: 7408029; 면적 유형: 건물 일반 면적; 용도분류코드: 070200
치수 - 계산 높이: 1000 mm; 둘레: 67400 mm; 면적: 264.078 m2

# IfcSpace: 판매시설 중 상점 18:7411260, 18
In: 지상 1층
LongName: 판매시설 중 상점; InteriorOrExteriorSpace: INTERNAL; Group: 용도구획
Pset_SpaceCommon - Reference: 판매시설 중 상점 18
BaseQuantities - NetFloorArea: 142.425 m2; Height: 4800 mm; GrossFloorArea: 142.425 m2; GrossVolume: 683.64 m3
ID 데이터 - 번호: 18; 이름: 판매시설 중 상점
구속조건 - 레벨: 지상 1층
기타 - 카테고리: 면적; 면적 양식 ID: 7408029; 면적 유형: 건물 일반 면적; 용도분류코드: 070200
치수 - 계산 높이: 1000 mm; 둘레: 48100 mm; 면적: 142.425 m2

# IfcSpace: 홀 134:3690451, 134
In: 지하2층
LongName: 홀; InteriorOrExteriorSpace: INTERNAL
Pset_SpaceCommon - Reference: 홀 134; FloorCovering: T80 화강석물갈기; WallCovering: T30화강석물갈기; CeilingCovering: 무늬코트뿜칠
BaseQuantities - NetFloorArea: 14.5677 m2; Height: 3850 mm; GrossPerimeter: 16543.7 mm; GrossFloorArea: 14.5677 m2; GrossVolume: 56.0855 m3
ID 데이터 - 바닥 마감: T80 화강석물갈기; 번호: 134; 베이스 마감: 목재 걸레받이; 벽 마감: T30화강석물갈기; 이름: 홀; 천장 마감: 무늬코트뿜칠
공정 - 공정: 새 구성
구속조건 - 베이스 간격띄우기: 0 mm; 상한값: 지하2층; 레벨: 지하2층; 한계 간격띄우기: 3850 mm
기타 - 거실여부: no; 공정 ID: 0; 카테고리: 룸; 공간분류코드: 33118; 실ID: B210
에너지 해석 - 구역별 실제 전력 부하: 0; 구역별 실제 조명 부하: 0; 기초 전력 부하: 공간 유형별; 기초 조명 부하: 공간 유형별; 사람 수: 0; 열 부하 값: 공간 유형별; 전력 부하 단위: 전력 밀도; 조명 부하 단위: 전력 밀도; 1인당 잠열 취득: 58.6142 W; 1인당 현열 취득: 73.2678 W; 개인별 면적: 28.5714 m2; 실제 전력 부하: 0 W; 실제 조명 부하: 0 W; 지정된 구역별 전력 부하: 13.9931; 지정된 구역별 조명 부하: 10.7639; 지정된 전력 부하: 0 W; 지정된 조명 부하: 0 W; 천장속 조명 방사: 20; 총 개인별 열 취득: 131.882 W
치수 - 계산 높이: 0 mm; 둘레: 16543.7 mm; 면적: 14.5677 m2; 무한한 높이: 3850 mm; 체적: 56.0855 m3

# IfcSpace: 홀 143:3691168, 143
In: 지하1층
LongName: 홀; InteriorOrExteriorSpace: INTERNAL
Pset_SpaceCommon - Reference: 홀 143; FloorCovering: T80 화강석물갈기; WallCovering: T30화강석물갈기; CeilingCovering: 무늬코트뿜칠
BaseQuantities - NetFloorArea: 14.5859 m2; Height: 5900 mm; GrossPerimeter: 16619.9 mm; GrossFloorArea: 14.5859 m2; GrossVolume: 86.057 m3
ID 데이터 - 바닥 마감: T80 화강석물갈기; 번호: 143; 베이스 마감: 목재 걸레받이; 벽 마감: T30화강석물갈기; 이름: 홀; 천장 마감: 무늬코트뿜칠
공정 - 공정: 새 구성
구속조건 - 베이스 간격띄우기: 0 mm; 상한값: 지하1층; 레벨: 지하1층; 한계 간격띄우기: 5900 mm
기타 - 거실여부: no; 공정 ID: 0; 카테고리: 룸; 공간분류코드: 33118; 실ID: B106
에너지 해석 - 구역별 실제 전력 부하: 0; 구역별 실제 조명 부하: 0; 기초 전력 부하: 공간 유형별; 기초 조명 부하: 공간 유형별; 사람 수: 0; 열 부하 값: 공간 유형별; 전력 부하 단위: 전력 밀도; 조명 부하 단위: 전력 밀도; 1인당 잠열 취득: 58.6142 W; 1인당 현열 취득: 73.2678 W; 개인별 면적: 28.5714 m2; 실제 전력 부하: 0 W; 실제 조명 부하: 0 W; 지정된 구역별 전력 부하: 13.9931; 지정된 구역별 조명 부하: 10.7639; 지정된 전력 부하: 0 W; 지정된 조명 부하: 0 W; 천장속 조명 방사: 20; 총 개인별 열 취득: 131.882 W
치수 - 계산 높이: 0 mm; 둘레: 16619.9 mm; 면적: 14.5859 m2; 무한한 높이: 5900 mm; 체적: 86.057 m3

# IfcSpace: 화장실(남) 171:3691289, 171
In: 지상 1층
LongName: 화장실(남); InteriorOrExteriorSpace: INTERNAL
Pset_SpaceCommon - Reference: 화장실(남) 171; FloorCovering: 자기질타일(바탕32, 압착8); WallCovering: 도기질타일(200x200x8T); CeilingCovering: 열경화성 천정재 (300x300x1.2T)
BaseQuantities - NetFloorArea: 11.0234 m2; Height: 2290 mm; GrossPerimeter: 13759.9 mm; GrossFloorArea: 11.0234 m2; GrossVolume: 25.2437 m3
ID 데이터 - 바닥 마감: 자기질타일(바탕32, 압착8); 번호: 171; 베이스 마감: 목재 걸레받이; 벽 마감: 도기질타일(200x200x8T); 이름: 화장실(남); 천장 마감: 열경화성 천정재 (300x300x1.2T)
공정 - 공정: 새 구성
구속조건 - 상한값: 지상 1층; 레벨: 지상 1층; 베이스 간격띄우기: -600 mm; 한계 간격띄우기: 1690 mm
기타 - 공정 ID: 0; 카테고리: 룸; 거실여부: yes; 방화구획: yes; 공간분류코드: 33234; 실ID: 122
에너지 해석 - 구역별 실제 전력 부하: 0; 구역별 실제 조명 부하: 0; 기초 전력 부하: 공간 유형별; 기초 조명 부하: 공간 유형별; 사람 수: 0; 열 부하 값: 공간 유형별; 전력 부하 단위: 전력 밀도; 조명 부하 단위: 전력 밀도; 1인당 잠열 취득: 58.6142 W; 1인당 현열 취득: 73.2678 W; 개인별 면적: 28.5714 m2; 실제 전력 부하: 0 W; 실제 조명 부하: 0 W; 지정된 구역별 전력 부하: 13.9931; 지정된 구역별 조명 부하: 10.7639; 지정된 전력 부하: 0 W; 지정된 조명 부하: 0 W; 천장속 조명 방사: 20; 총 개인별 열 취득: 131.882 W
치수 - 계산 높이: 1000 mm; 둘레: 13759.9 mm; 면적: 11.0234 m2; 무한한 높이: 2290 mm; 체적: 25.2437 m3

# IfcSpace: 화장실(남) 189:3691558, 189
In: 지상 2층
LongName: 화장실(남); InteriorOrExteriorSpace: INTERNAL
Pset_SpaceCommon - Reference: 화장실(남) 189; FloorCovering: 자기질타일(바탕32, 압착8); WallCovering: 도기질타일(200x200x8T); CeilingCovering: 열경화성 천정재 (300x300x1.2T)
BaseQuantities - NetFloorArea: 11.0234 m2; Height: 2710 mm; GrossPerimeter: 13759.9 mm; GrossFloorArea: 11.0234 m2; GrossVolume: 29.8735 m3
ID 데이터 - 바닥 마감: 자기질타일(바탕32, 압착8); 번호: 189; 베이스 마감: 목재 걸레받이; 벽 마감: 도기질타일(200x200x8T); 이름: 화장실(남); 천장 마감: 열경화성 천정재 (300x300x1.2T)
공정 - 공정: 새 구성
구속조건 - 상한값: 지상 2층; 레벨: 지상 2층; 베이스 간격띄우기: -50 mm; 한계 간격띄우기: 2660 mm
기타 - 공정 ID: 0; 카테고리: 룸; 거실여부: yes; 방화구획: yes; 공간분류코드: 33234; 실ID: 211
에너지 해석 - 구역별 실제 전력 부하: 0; 구역별 실제 조명 부하: 0; 기초 전력 부하: 공간 유형별; 기초 조명 부하: 공간 유형별; 사람 수: 0; 열 부하 값: 공간 유형별; 전력 부하 단위: 전력 밀도; 조명 부하 단위: 전력 밀도; 1인당 잠열 취득: 58.6142 W; 1인당 현열 취득: 73.2678 W; 개인별 면적: 28.5714 m2; 실제 전력 부하: 0 W; 실제 조명 부하: 0 W; 지정된 구역별 전력 부하: 13.9931; 지정된 구역별 조명 부하: 10.7639; 지정된 전력 부하: 0 W; 지정된 조명 부하: 0 W; 천장속 조명 방사: 20; 총 개인별 열 취득: 131.882 W
치수 - 계산 높이: 1000 mm; 둘레: 13759.9 mm; 면적: 11.0234 m2; 무한한 높이: 2710 mm; 체적: 29.8735 m3

# IfcSpace: 화장실(남) 203:3691792, 203
In: 지상 3층
LongName: 화장실(남); InteriorOrExteriorSpace: INTERNAL
Pset_SpaceCommon - Reference: 화장실(남) 203; FloorCovering: 자기질타일(바탕32, 압착8); WallCovering: 도기질타일(200x200x8T); CeilingCovering: 열경화성 천정재 (300x300x1.2T)
BaseQuantities - NetFloorArea: 11.0234 m2; Height: 2710 mm; GrossPerimeter: 13759.9 mm; GrossFloorArea: 11.0234 m2; GrossVolume: 29.8735 m3
ID 데이터 - 바닥 마감: 자기질타일(바탕32, 압착8); 번호: 203; 베이스 마감: 목재 걸레받이; 벽 마감: 도기질타일(200x200x8T); 이름: 화장실(남); 천장 마감: 열경화성 천정재 (300x300x1.2T)
공정 - 공정: 새 구성
구속조건 - 상한값: 지상 3층; 레벨: 지상 3층; 베이스 간격띄우기: -50 mm; 한계 간격띄우기: 2660 mm
기타 - 공정 ID: 0; 카테고리: 룸; 거실여부: yes; 방화구획: yes; 공간분류코드: 33234; 실ID: 312
에너지 해석 - 구역별 실제 전력 부하: 0; 구역별 실제 조명 부하: 0; 기초 전력 부하: 공간 유형별; 기초 조명 부하: 공간 유형별; 사람 수: 0; 열 부하 값: 공간 유형별; 전력 부하 단위: 전력 밀도; 조명 부하 단위: 전력 밀도; 1인당 잠열 취득: 58.6142 W; 1인당 현열 취득: 73.2678 W; 개인별 면적: 28.5714 m2; 실제 전력 부하: 0 W; 실제 조명 부하: 0 W; 지정된 구역별 전력 부하: 13.9931; 지정된 구역별 조명 부하: 10.7639; 지정된 전력 부하: 0 W; 지정된 조명 부하: 0 W; 천장속 조명 방사: 20; 총 개인별 열 취득: 131.882 W
치수 - 계산 높이: 1000 mm; 둘레: 13759.9 mm; 면적: 11.0234 m2; 무한한 높이: 2710 mm; 체적: 29.8735 m3

# IfcSpace: 화장실(남) 221:3692897, 221
In: 지상 4층
LongName: 화장실(남); InteriorOrExteriorSpace: INTERNAL
Pset_SpaceCommon - Reference: 화장실(남) 221; FloorCovering: 자기질타일(바탕32, 압착8); WallCovering: 도기질타일(200x200x8T); CeilingCovering: 열경화성 천정재 (300x300x1.2T)
BaseQuantities - NetFloorArea: 11.0234 m2; Height: 2710 mm; GrossPerimeter: 13759.9 mm; GrossFloorArea: 11.0234 m2; GrossVolume: 29.8735 m3
ID 데이터 - 바닥 마감: 자기질타일(바탕32, 압착8); 번호: 221; 베이스 마감: 목재 걸레받이; 벽 마감: 도기질타일(200x200x8T); 이름: 화장실(남); 천장 마감: 열경화성 천정재 (300x300x1.2T)
공정 - 공정: 새 구성
구속조건 - 상한값: 지상 4층; 레벨: 지상 4층; 베이스 간격띄우기: -50 mm; 한계 간격띄우기: 2660 mm
기타 - 공정 ID: 0; 카테고리: 룸; 거실여부: yes; 방화구획: yes; 공간분류코드: 33234; 실ID: 410
에너지 해석 - 구역별 실제 전력 부하: 0; 구역별 실제 조명 부하: 0; 기초 전력 부하: 공간 유형별; 기초 조명 부하: 공간 유형별; 사람 수: 0; 열 부하 값: 공간 유형별; 전력 부하 단위: 전력 밀도; 조명 부하 단위: 전력 밀도; 1인당 잠열 취득: 58.6142 W; 1인당 현열 취득: 73.2678 W; 개인별 면적: 28.5714 m2; 실제 전력 부하: 0 W; 실제 조명 부하: 0 W; 지정된 구역별 전력 부하: 13.9931; 지정된 구역별 조명 부하: 10.7639; 지정된 전력 부하: 0 W; 지정된 조명 부하: 0 W; 천장속 조명 방사: 20; 총 개인별 열 취득: 131.882 W
치수 - 계산 높이: 1000 mm; 둘레: 13759.9 mm; 면적: 11.0234 m2; 무한한 높이: 2710 mm; 체적: 29.8735 m3

# IfcSpace: 화장실(남) 226:3692922, 226
In: 지상 5층
LongName: 화장실(남); InteriorOrExteriorSpace: INTERNAL
Pset_SpaceCommon - Reference: 화장실(남) 226; FloorCovering: 자기질타일(바탕32, 압착8); WallCovering: 도기질타일(200x200x8T); CeilingCovering: 열경화성 천정재 (300x300x1.2T)
BaseQuantities - NetFloorArea: 11.0234 m2; Height: 2710 mm; GrossPerimeter: 13759.9 mm; GrossFloorArea: 11.0234 m2; GrossVolume: 29.8735 m3
ID 데이터 - 바닥 마감: 자기질타일(바탕32, 압착8); 번호: 226; 베이스 마감: 목재 걸레받이; 벽 마감: 도기질타일(200x200x8T); 이름: 화장실(남); 천장 마감: 열경화성 천정재 (300x300x1.2T)
공정 - 공정: 새 구성
구속조건 - 상한값: 지상 5층; 레벨: 지상 5층; 베이스 간격띄우기: -50 mm; 한계 간격띄우기: 2660 mm
기타 - 공정 ID: 0; 카테고리: 룸; 거실여부: yes; 방화구획: yes; 공간분류코드: 33234; 실ID: 503
에너지 해석 - 구역별 실제 전력 부하: 0; 구역별 실제 조명 부하: 0; 기초 전력 부하: 공간 유형별; 기초 조명 부하: 공간 유형별; 사람 수: 0; 열 부하 값: 공간 유형별; 전력 부하 단위: 전력 밀도; 조명 부하 단위: 전력 밀도; 1인당 잠열 취득: 58.6142 W; 1인당 현열 취득: 73.2678 W; 개인별 면적: 28.5714 m2; 실제 전력 부하: 0 W; 실제 조명 부하: 0 W; 지정된 구역별 전력 부하: 13.9931; 지정된 구역별 조명 부하: 10.7639; 지정된 전력 부하: 0 W; 지정된 조명 부하: 0 W; 천장속 조명 방사: 20; 총 개인별 열 취득: 131.882 W
치수 - 계산 높이: 1000 mm; 둘레: 13759.9 mm; 면적: 11.0234 m2; 무한한 높이: 2710 mm; 체적: 29.8735 m3

# IfcSpace: 화장실(남) 241:3694125, 241
In: 지상 6층
LongName: 화장실(남); InteriorOrExteriorSpace: INTERNAL
Pset_SpaceCommon - Reference: 화장실(남) 241; FloorCovering: 자기질타일(바탕32, 압착8); WallCovering: 도기질타일(200x200x8T); CeilingCovering: 열경화성 천정재 (300x300x1.2T)
BaseQuantities - NetFloorArea: 11.0236 m2; Height: 2710 mm; GrossPerimeter: 13760 mm; GrossFloorArea: 11.0236 m2; GrossVolume: 29.874 m3
ID 데이터 - 바닥 마감: 자기질타일(바탕32, 압착8); 번호: 241; 베이스 마감: 목재 걸레받이; 벽 마감: 도기질타일(200x200x8T); 이름: 화장실(남); 천장 마감: 열경화성 천정재 (300x300x1.2T)
공정 - 공정: 새 구성
구속조건 - 상한값: 지상 6층; 레벨: 지상 6층; 베이스 간격띄우기: -50 mm; 한계 간격띄우기: 2660 mm
기타 - 공정 ID: 0; 카테고리: 룸; 거실여부: yes; 방화구획: yes; 공간분류코드: 33234; 실ID: 603
에너지 해석 - 구역별 실제 전력 부하: 0; 구역별 실제 조명 부하: 0; 기초 전력 부하: 공간 유형별; 기초 조명 부하: 공간 유형별; 사람 수: 0; 열 부하 값: 공간 유형별; 전력 부하 단위: 전력 밀도; 조명 부하 단위: 전력 밀도; 1인당 잠열 취득: 58.6142 W; 1인당 현열 취득: 73.2678 W; 개인별 면적: 28.5714 m2; 실제 전력 부하: 0 W; 실제 조명 부하: 0 W; 지정된 구역별 전력 부하: 13.9931; 지정된 구역별 조명 부하: 10.7639; 지정된 전력 부하: 0 W; 지정된 조명 부하: 0 W; 천장속 조명 방사: 20; 총 개인별 열 취득: 131.882 W
치수 - 계산 높이: 1000 mm; 둘레: 13760 mm; 면적: 11.0236 m2; 무한한 높이: 2710 mm; 체적: 29.874 m3

# IfcSpace: 화장실(남) 267:3694364, 267
In: 지상 7층
LongName: 화장실(남); InteriorOrExteriorSpace: INTERNAL
Pset_SpaceCommon - Reference: 화장실(남) 267; FloorCovering: 자기질타일(바탕32, 압착8); WallCovering: 도기질타일(200x200x8T); CeilingCovering: 열경화성 천정재 (300x300x1.2T)
BaseQuantities - NetFloorArea: 11.0234 m2; Height: 2710 mm; GrossPerimeter: 13759.9 mm; GrossFloorArea: 11.0234 m2; GrossVolume: 29.8735 m3
ID 데이터 - 바닥 마감: 자기질타일(바탕32, 압착8); 번호: 267; 베이스 마감: 목재 걸레받이; 벽 마감: 도기질타일(200x200x8T); 이름: 화장실(남); 천장 마감: 열경화성 천정재 (300x300x1.2T)
공정 - 공정: 새 구성
구속조건 - 상한값: 지상 7층; 레벨: 지상 7층; 베이스 간격띄우기: -50 mm; 한계 간격띄우기: 2660 mm
기타 - 공정 ID: 0; 카테고리: 룸; 거실여부: yes; 방화구획: yes; 공간분류코드: 33234; 실ID: 712
에너지 해석 - 구역별 실제 전력 부하: 0; 구역별 실제 조명 부하: 0; 기초 전력 부하: 공간 유형별; 기초 조명 부하: 공간 유형별; 사람 수: 0; 열 부하 값: 공간 유형별; 전력 부하 단위: 전력 밀도; 조명 부하 단위: 전력 밀도; 1인당 잠열 취득: 58.6142 W; 1인당 현열 취득: 73.2678 W; 개인별 면적: 28.5714 m2; 실제 전력 부하: 0 W; 실제 조명 부하: 0 W; 지정된 구역별 전력 부하: 13.9931; 지정된 구역별 조명 부하: 10.7639; 지정된 전력 부하: 0 W; 지정된 조명 부하: 0 W; 천장속 조명 방사: 20; 총 개인별 열 취득: 131.882 W
치수 - 계산 높이: 1000 mm; 둘레: 13759.9 mm; 면적: 11.0234 m2; 무한한 높이: 2710 mm; 체적: 29.8735 m3

# IfcSpace: 화장실(남) 279:3694563, 279
In: 지상 8층
LongName: 화장실(남); InteriorOrExteriorSpace: INTERNAL
Pset_SpaceCommon - Reference: 화장실(남) 279; FloorCovering: 자기질타일(바탕32, 압착8); WallCovering: 도기질타일(200x200x8T); CeilingCovering: 열경화성 천정재 (300x300x1.2T)
BaseQuantities - NetFloorArea: 11.0234 m2; Height: 2710 mm; GrossPerimeter: 13759.9 mm; GrossFloorArea: 11.0234 m2; GrossVolume: 29.8735 m3
ID 데이터 - 바닥 마감: 자기질타일(바탕32, 압착8); 번호: 279; 베이스 마감: 목재 걸레받이; 벽 마감: 도기질타일(200x200x8T); 이름: 화장실(남); 천장 마감: 열경화성 천정재 (300x300x1.2T)
공정 - 공정: 새 구성
구속조건 - 상한값: 지상 8층; 레벨: 지상 8층; 베이스 간격띄우기: -50 mm; 한계 간격띄우기: 2660 mm
기타 - 공정 ID: 0; 카테고리: 룸; 거실여부: yes; 공간분류코드: 33234; 실ID: 806
에너지 해석 - 구역별 실제 전력 부하: 0; 구역별 실제 조명 부하: 0; 기초 전력 부하: 공간 유형별; 기초 조명 부하: 공간 유형별; 사람 수: 0; 열 부하 값: 공간 유형별; 전력 부하 단위: 전력 밀도; 조명 부하 단위: 전력 밀도; 1인당 잠열 취득: 58.6142 W; 1인당 현열 취득: 73.2678 W; 개인별 면적: 28.5714 m2; 실제 전력 부하: 0 W; 실제 조명 부하: 0 W; 지정된 구역별 전력 부하: 13.9931; 지정된 구역별 조명 부하: 10.7639; 지정된 전력 부하: 0 W; 지정된 조명 부하: 0 W; 천장속 조명 방사: 20; 총 개인별 열 취득: 131.882 W
치수 - 계산 높이: 1000 mm; 둘레: 13759.9 mm; 면적: 11.0234 m2; 무한한 높이: 2710 mm; 체적: 29.8735 m3

# IfcSpace: 화장실(남) 298:3694759, 298
In: 지상 9층
LongName: 화장실(남); InteriorOrExteriorSpace: INTERNAL
Pset_SpaceCommon - Reference: 화장실(남) 298; FloorCovering: 자기질타일(바탕32, 압착8); WallCovering: 도기질타일(200x200x8T); CeilingCovering: 열경화성 천정재 (300x300x1.2T)
BaseQuantities - NetFloorArea: 11.0234 m2; Height: 2710 mm; GrossPerimeter: 13759.9 mm; GrossFloorArea: 11.0234 m2; GrossVolume: 29.8735 m3
ID 데이터 - 바닥 마감: 자기질타일(바탕32, 압착8); 번호: 298; 베이스 마감: 목재 걸레받이; 벽 마감: 도기질타일(200x200x8T); 이름: 화장실(남); 천장 마감: 열경화성 천정재 (300x300x1.2T)
공정 - 공정: 새 구성
구속조건 - 상한값: 지상 9층; 레벨: 지상 9층; 베이스 간격띄우기: -50 mm; 한계 간격띄우기: 2660 mm
기타 - 공정 ID: 0; 카테고리: 룸; 거실여부: yes; 공간분류코드: 33234; 실ID: 909
에너지 해석 - 구역별 실제 전력 부하: 0; 구역별 실제 조명 부하: 0; 기초 전력 부하: 공간 유형별; 기초 조명 부하: 공간 유형별; 사람 수: 0; 열 부하 값: 공간 유형별; 전력 부하 단위: 전력 밀도; 조명 부하 단위: 전력 밀도; 1인당 잠열 취득: 58.6142 W; 1인당 현열 취득: 73.2678 W; 개인별 면적: 28.5714 m2; 실제 전력 부하: 0 W; 실제 조명 부하: 0 W; 지정된 구역별 전력 부하: 13.9931; 지정된 구역별 조명 부하: 10.7639; 지정된 전력 부하: 0 W; 지정된 조명 부하: 0 W; 천장속 조명 방사: 20; 총 개인별 열 취득: 131.882 W
치수 - 계산 높이: 1000 mm; 둘레: 13759.9 mm; 면적: 11.0234 m2; 무한한 높이: 2710 mm; 체적: 29.8735 m3

# IfcSpace: 화장실(남) 313:3694940, 313
In: 지상 10층
LongName: 화장실(남); InteriorOrExteriorSpace: INTERNAL
Pset_SpaceCommon - Reference: 화장실(남) 313; FloorCovering: 자기질타일(바탕32, 압착8); WallCovering: 도기질타일(200x200x8T); CeilingCovering: 열경화성 천정재 (300x300x1.2T)
BaseQuantities - NetFloorArea: 11.013 m2; Height: 2710 mm; GrossFloorArea: 11.013 m2; GrossVolume: 29.8452 m3
ID 데이터 - 바닥 마감: 자기질타일(바탕32, 압착8); 번호: 313; 베이스 마감: 목재 걸레받이; 벽 마감: 도기질타일(200x200x8T); 이름: 화장실(남); 천장 마감: 열경화성 천정재 (300x300x1.2T)
공정 - 공정: 새 구성
구속조건 - 상한값: 지상 10층; 레벨: 지상 10층; 베이스 간격띄우기: -50 mm; 한계 간격띄우기: 2660 mm
기타 - 공정 ID: 0; 카테고리: 룸; 거실여부: yes; 공간분류코드: 33234; 실ID: 1009
에너지 해석 - 구역별 실제 전력 부하: 0; 구역별 실제 조명 부하: 0; 기초 전력 부하: 공간 유형별; 기초 조명 부하: 공간 유형별; 사람 수: 0; 열 부하 값: 공간 유형별; 전력 부하 단위: 전력 밀도; 조명 부하 단위: 전력 밀도; 1인당 잠열 취득: 58.6142 W; 1인당 현열 취득: 73.2678 W; 개인별 면적: 28.5714 m2; 실제 전력 부하: 0 W; 실제 조명 부하: 0 W; 지정된 구역별 전력 부하: 13.9931; 지정된 구역별 조명 부하: 10.7639; 지정된 전력 부하: 0 W; 지정된 조명 부하: 0 W; 천장속 조명 방사: 20; 총 개인별 열 취득: 131.882 W
치수 - 계산 높이: 1000 mm; 둘레: 13688 mm; 면적: 11.013 m2; 무한한 높이: 2710 mm; 체적: 28.4135 m3

# IfcSpace: 화장실(여) 170:3691286, 170
In: 지상 1층
LongName: 화장실(여); InteriorOrExteriorSpace: INTERNAL
Pset_SpaceCommon - Reference: 화장실(여) 170; FloorCovering: 자기질타일(바탕32, 압착8); WallCovering: 도기질타일(200x200x8T); CeilingCovering: 열경화성 천정재 (300x300x1.2T)
BaseQuantities - NetFloorArea: 16.7538 m2; Height: 2290 mm; GrossPerimeter: 21529.9 mm; GrossFloorArea: 16.7538 m2; GrossVolume: 38.3661 m3
ID 데이터 - 바닥 마감: 자기질타일(바탕32, 압착8); 번호: 170; 베이스 마감: 목재 걸레받이; 벽 마감: 도기질타일(200x200x8T); 이름: 화장실(여); 천장 마감: 열경화성 천정재 (300x300x1.2T)
공정 - 공정: 새 구성
구속조건 - 상한값: 지상 1층; 레벨: 지상 1층; 베이스 간격띄우기: -600 mm; 한계 간격띄우기: 1690 mm
기타 - 공정 ID: 0; 카테고리: 룸; 거실여부: yes; 방화구획: yes; 공간분류코드: 33234; 실ID: 121
에너지 해석 - 구역별 실제 전력 부하: 0; 구역별 실제 조명 부하: 0; 기초 전력 부하: 공간 유형별; 기초 조명 부하: 공간 유형별; 사람 수: 0; 열 부하 값: 공간 유형별; 전력 부하 단위: 전력 밀도; 조명 부하 단위: 전력 밀도; 1인당 잠열 취득: 58.6142 W; 1인당 현열 취득: 73.2678 W; 개인별 면적: 28.5714 m2; 실제 전력 부하: 0 W; 실제 조명 부하: 0 W; 지정된 구역별 전력 부하: 13.9931; 지정된 구역별 조명 부하: 10.7639; 지정된 전력 부하: 0 W; 지정된 조명 부하: 0 W; 천장속 조명 방사: 20; 총 개인별 열 취득: 131.882 W
치수 - 계산 높이: 1000 mm; 둘레: 21529.9 mm; 면적: 16.7538 m2; 무한한 높이: 2290 mm; 체적: 38.3661 m3

# IfcSpace: 화장실(여) 202:3691789, 202
In: 지상 3층
LongName: 화장실(여); InteriorOrExteriorSpace: INTERNAL
Pset_SpaceCommon - Reference: 화장실(여) 202; FloorCovering: 자기질타일(바탕32, 압착8); WallCovering: 도기질타일(200x200x8T); CeilingCovering: 열경화성 천정재 (300x300x1.2T)
BaseQuantities - NetFloorArea: 16.7538 m2; Height: 2710 mm; GrossPerimeter: 21529.9 mm; GrossFloorArea: 16.7538 m2; GrossVolume: 45.4027 m3
ID 데이터 - 바닥 마감: 자기질타일(바탕32, 압착8); 번호: 202; 베이스 마감: 목재 걸레받이; 벽 마감: 도기질타일(200x200x8T); 이름: 화장실(여); 천장 마감: 열경화성 천정재 (300x300x1.2T)
공정 - 공정: 새 구성
구속조건 - 상한값: 지상 3층; 레벨: 지상 3층; 베이스 간격띄우기: -50 mm; 한계 간격띄우기: 2660 mm
기타 - 공정 ID: 0; 카테고리: 룸; 거실여부: yes; 방화구획: yes; 공간분류코드: 33234; 실ID: 311
에너지 해석 - 구역별 실제 전력 부하: 0; 구역별 실제 조명 부하: 0; 기초 전력 부하: 공간 유형별; 기초 조명 부하: 공간 유형별; 사람 수: 0; 열 부하 값: 공간 유형별; 전력 부하 단위: 전력 밀도; 조명 부하 단위: 전력 밀도; 1인당 잠열 취득: 58.6142 W; 1인당 현열 취득: 73.2678 W; 개인별 면적: 28.5714 m2; 실제 전력 부하: 0 W; 실제 조명 부하: 0 W; 지정된 구역별 전력 부하: 13.9931; 지정된 구역별 조명 부하: 10.7639; 지정된 전력 부하: 0 W; 지정된 조명 부하: 0 W; 천장속 조명 방사: 20; 총 개인별 열 취득: 131.882 W
치수 - 계산 높이: 1000 mm; 둘레: 21529.9 mm; 면적: 16.7538 m2; 무한한 높이: 2710 mm; 체적: 45.4027 m3

# IfcSpace: 화장실(여) 222:3692900, 222
In: 지상 4층
LongName: 화장실(여); InteriorOrExteriorSpace: INTERNAL
Pset_SpaceCommon - Reference: 화장실(여) 222; FloorCovering: 자기질타일(바탕32, 압착8); WallCovering: 도기질타일(200x200x8T); CeilingCovering: 열경화성 천정재 (300x300x1.2T)
BaseQuantities - NetFloorArea: 16.7538 m2; Height: 2710 mm; GrossPerimeter: 21529.9 mm; GrossFloorArea: 16.7538 m2; GrossVolume: 45.4027 m3
ID 데이터 - 바닥 마감: 자기질타일(바탕32, 압착8); 번호: 222; 베이스 마감: 목재 걸레받이; 벽 마감: 도기질타일(200x200x8T); 이름: 화장실(여); 천장 마감: 열경화성 천정재 (300x300x1.2T)
공정 - 공정: 새 구성
구속조건 - 상한값: 지상 4층; 레벨: 지상 4층; 베이스 간격띄우기: -50 mm; 한계 간격띄우기: 2660 mm
기타 - 공정 ID: 0; 카테고리: 룸; 거실여부: yes; 방화구획: yes; 공간분류코드: 33234; 실ID: 411
에너지 해석 - 구역별 실제 전력 부하: 0; 구역별 실제 조명 부하: 0; 기초 전력 부하: 공간 유형별; 기초 조명 부하: 공간 유형별; 사람 수: 0; 열 부하 값: 공간 유형별; 전력 부하 단위: 전력 밀도; 조명 부하 단위: 전력 밀도; 1인당 잠열 취득: 58.6142 W; 1인당 현열 취득: 73.2678 W; 개인별 면적: 28.5714 m2; 실제 전력 부하: 0 W; 실제 조명 부하: 0 W; 지정된 구역별 전력 부하: 13.9931; 지정된 구역별 조명 부하: 10.7639; 지정된 전력 부하: 0 W; 지정된 조명 부하: 0 W; 천장속 조명 방사: 20; 총 개인별 열 취득: 131.882 W
치수 - 계산 높이: 1000 mm; 둘레: 21529.9 mm; 면적: 16.7538 m2; 무한한 높이: 2710 mm; 체적: 45.4027 m3

# IfcSpace: 화장실(여) 225:3692919, 225
In: 지상 5층
LongName: 화장실(여); InteriorOrExteriorSpace: INTERNAL
Pset_SpaceCommon - Reference: 화장실(여) 225; FloorCovering: 자기질타일(바탕32, 압착8); WallCovering: 도기질타일(200x200x8T); CeilingCovering: 열경화성 천정재 (300x300x1.2T)
BaseQuantities - NetFloorArea: 16.7538 m2; Height: 2710 mm; GrossPerimeter: 21529.9 mm; GrossFloorArea: 16.7538 m2; GrossVolume: 45.4027 m3
ID 데이터 - 바닥 마감: 자기질타일(바탕32, 압착8); 번호: 225; 베이스 마감: 목재 걸레받이; 벽 마감: 도기질타일(200x200x8T); 이름: 화장실(여); 천장 마감: 열경화성 천정재 (300x300x1.2T)
공정 - 공정: 새 구성
구속조건 - 상한값: 지상 5층; 레벨: 지상 5층; 베이스 간격띄우기: -50 mm; 한계 간격띄우기: 2660 mm
기타 - 공정 ID: 0; 카테고리: 룸; 거실여부: yes; 방화구획: yes; 공간분류코드: 33234; 실ID: 502
에너지 해석 - 구역별 실제 전력 부하: 0; 구역별 실제 조명 부하: 0; 기초 전력 부하: 공간 유형별; 기초 조명 부하: 공간 유형별; 사람 수: 0; 열 부하 값: 공간 유형별; 전력 부하 단위: 전력 밀도; 조명 부하 단위: 전력 밀도; 1인당 잠열 취득: 58.6142 W; 1인당 현열 취득: 73.2678 W; 개인별 면적: 28.5714 m2; 실제 전력 부하: 0 W; 실제 조명 부하: 0 W; 지정된 구역별 전력 부하: 13.9931; 지정된 구역별 조명 부하: 10.7639; 지정된 전력 부하: 0 W; 지정된 조명 부하: 0 W; 천장속 조명 방사: 20; 총 개인별 열 취득: 131.882 W
치수 - 계산 높이: 1000 mm; 둘레: 21529.9 mm; 면적: 16.7538 m2; 무한한 높이: 2710 mm; 체적: 45.4027 m3

# IfcSpace: 화장실(여) 240:3694123, 240
In: 지상 6층
LongName: 화장실(여); InteriorOrExteriorSpace: INTERNAL
Pset_SpaceCommon - Reference: 화장실(여) 240; FloorCovering: 자기질타일(바탕32, 압착8); WallCovering: 도기질타일(200x200x8T); CeilingCovering: 열경화성 천정재 (300x300x1.2T)
BaseQuantities - NetFloorArea: 16.7538 m2; Height: 2710 mm; GrossPerimeter: 21529.9 mm; GrossFloorArea: 16.7538 m2; GrossVolume: 45.4027 m3
ID 데이터 - 바닥 마감: 자기질타일(바탕32, 압착8); 번호: 240; 베이스 마감: 목재 걸레받이; 벽 마감: 도기질타일(200x200x8T); 이름: 화장실(여); 천장 마감: 열경화성 천정재 (300x300x1.2T)
공정 - 공정: 새 구성
구속조건 - 상한값: 지상 6층; 레벨: 지상 6층; 베이스 간격띄우기: -50 mm; 한계 간격띄우기: 2660 mm
기타 - 공정 ID: 0; 카테고리: 룸; 거실여부: yes; 방화구획: yes; 공간분류코드: 33234; 실ID: 602
에너지 해석 - 구역별 실제 전력 부하: 0; 구역별 실제 조명 부하: 0; 기초 전력 부하: 공간 유형별; 기초 조명 부하: 공간 유형별; 사람 수: 0; 열 부하 값: 공간 유형별; 전력 부하 단위: 전력 밀도; 조명 부하 단위: 전력 밀도; 1인당 잠열 취득: 58.6142 W; 1인당 현열 취득: 73.2678 W; 개인별 면적: 28.5714 m2; 실제 전력 부하: 0 W; 실제 조명 부하: 0 W; 지정된 구역별 전력 부하: 13.9931; 지정된 구역별 조명 부하: 10.7639; 지정된 전력 부하: 0 W; 지정된 조명 부하: 0 W; 천장속 조명 방사: 20; 총 개인별 열 취득: 131.882 W
치수 - 계산 높이: 1000 mm; 둘레: 21529.9 mm; 면적: 16.7538 m2; 무한한 높이: 2710 mm; 체적: 45.4027 m3

# IfcSpace: 화장실(여) 266:3694361, 266
In: 지상 7층
LongName: 화장실(여); InteriorOrExteriorSpace: INTERNAL
Pset_SpaceCommon - Reference: 화장실(여) 266; FloorCovering: 자기질타일(바탕32, 압착8); WallCovering: 도기질타일(200x200x8T); CeilingCovering: 열경화성 천정재 (300x300x1.2T)
BaseQuantities - NetFloorArea: 16.7538 m2; Height: 2438.4 mm; GrossPerimeter: 21529.9 mm; GrossFloorArea: 16.7538 m2; GrossVolume: 40.8524 m3
ID 데이터 - 바닥 마감: 자기질타일(바탕32, 압착8); 번호: 266; 베이스 마감: 목재 걸레받이; 벽 마감: 도기질타일(200x200x8T); 이름: 화장실(여); 천장 마감: 열경화성 천정재 (300x300x1.2T)
공정 - 공정: 새 구성
구속조건 - 베이스 간격띄우기: 0 mm; 한계 간격띄우기: 2438.4 mm; 상한값: 지상 7층; 레벨: 지상 7층
기타 - 공정 ID: 0; 카테고리: 룸; 거실여부: yes; 방화구획: yes; 공간분류코드: 33234; 실ID: 711
에너지 해석 - 구역별 실제 전력 부하: 0; 구역별 실제 조명 부하: 0; 기초 전력 부하: 공간 유형별; 기초 조명 부하: 공간 유형별; 사람 수: 0; 열 부하 값: 공간 유형별; 전력 부하 단위: 전력 밀도; 조명 부하 단위: 전력 밀도; 1인당 잠열 취득: 58.6142 W; 1인당 현열 취득: 73.2678 W; 개인별 면적: 28.5714 m2; 실제 전력 부하: 0 W; 실제 조명 부하: 0 W; 지정된 구역별 전력 부하: 13.9931; 지정된 구역별 조명 부하: 10.7639; 지정된 전력 부하: 0 W; 지정된 조명 부하: 0 W; 천장속 조명 방사: 20; 총 개인별 열 취득: 131.882 W
치수 - 무한한 높이: 2438.4 mm; 계산 높이: 1000 mm; 둘레: 21529.9 mm; 면적: 16.7538 m2; 체적: 40.8524 m3

# IfcSpace: 화장실(여) 278:3694560, 278
In: 지상 8층
LongName: 화장실(여); InteriorOrExteriorSpace: INTERNAL
Pset_SpaceCommon - Reference: 화장실(여) 278; FloorCovering: 자기질타일(바탕32, 압착8); WallCovering: 도기질타일(200x200x8T); CeilingCovering: 열경화성 천정재 (300x300x1.2T)
BaseQuantities - NetFloorArea: 16.7538 m2; Height: 2710 mm; GrossPerimeter: 21529.9 mm; GrossFloorArea: 16.7538 m2; GrossVolume: 45.4027 m3
ID 데이터 - 바닥 마감: 자기질타일(바탕32, 압착8); 번호: 278; 베이스 마감: 목재 걸레받이; 벽 마감: 도기질타일(200x200x8T); 이름: 화장실(여); 천장 마감: 열경화성 천정재 (300x300x1.2T)
공정 - 공정: 새 구성
구속조건 - 상한값: 지상 8층; 레벨: 지상 8층; 베이스 간격띄우기: -50 mm; 한계 간격띄우기: 2660 mm
기타 - 공정 ID: 0; 카테고리: 룸; 거실여부: yes; 공간분류코드: 33234; 실ID: 805
에너지 해석 - 구역별 실제 전력 부하: 0; 구역별 실제 조명 부하: 0; 기초 전력 부하: 공간 유형별; 기초 조명 부하: 공간 유형별; 사람 수: 0; 열 부하 값: 공간 유형별; 전력 부하 단위: 전력 밀도; 조명 부하 단위: 전력 밀도; 1인당 잠열 취득: 58.6142 W; 1인당 현열 취득: 73.2678 W; 개인별 면적: 28.5714 m2; 실제 전력 부하: 0 W; 실제 조명 부하: 0 W; 지정된 구역별 전력 부하: 13.9931; 지정된 구역별 조명 부하: 10.7639; 지정된 전력 부하: 0 W; 지정된 조명 부하: 0 W; 천장속 조명 방사: 20; 총 개인별 열 취득: 131.882 W
치수 - 계산 높이: 1000 mm; 둘레: 21529.9 mm; 면적: 16.7538 m2; 무한한 높이: 2710 mm; 체적: 45.4027 m3

# IfcSpace: 화장실(여) 297:3694756, 297
In: 지상 9층
LongName: 화장실(여); InteriorOrExteriorSpace: INTERNAL
Pset_SpaceCommon - Reference: 화장실(여) 297; FloorCovering: 자기질타일(바탕32, 압착8); WallCovering: 도기질타일(200x200x8T); CeilingCovering: 열경화성 천정재 (300x300x1.2T)
BaseQuantities - NetFloorArea: 16.7538 m2; Height: 2710 mm; GrossPerimeter: 21529.9 mm; GrossFloorArea: 16.7538 m2; GrossVolume: 45.4027 m3
ID 데이터 - 바닥 마감: 자기질타일(바탕32, 압착8); 번호: 297; 베이스 마감: 목재 걸레받이; 벽 마감: 도기질타일(200x200x8T); 이름: 화장실(여); 천장 마감: 열경화성 천정재 (300x300x1.2T)
공정 - 공정: 새 구성
구속조건 - 상한값: 지상 9층; 레벨: 지상 9층; 베이스 간격띄우기: -50 mm; 한계 간격띄우기: 2660 mm
기타 - 공정 ID: 0; 카테고리: 룸; 거실여부: yes; 공간분류코드: 33234; 실ID: 908
에너지 해석 - 구역별 실제 전력 부하: 0; 구역별 실제 조명 부하: 0; 기초 전력 부하: 공간 유형별; 기초 조명 부하: 공간 유형별; 사람 수: 0; 열 부하 값: 공간 유형별; 전력 부하 단위: 전력 밀도; 조명 부하 단위: 전력 밀도; 1인당 잠열 취득: 58.6142 W; 1인당 현열 취득: 73.2678 W; 개인별 면적: 28.5714 m2; 실제 전력 부하: 0 W; 실제 조명 부하: 0 W; 지정된 구역별 전력 부하: 13.9931; 지정된 구역별 조명 부하: 10.7639; 지정된 전력 부하: 0 W; 지정된 조명 부하: 0 W; 천장속 조명 방사: 20; 총 개인별 열 취득: 131.882 W
치수 - 계산 높이: 1000 mm; 둘레: 21529.9 mm; 면적: 16.7538 m2; 무한한 높이: 2710 mm; 체적: 45.4027 m3

# IfcSpace: 화장실(여) 312:3694937, 312
In: 지상 10층
LongName: 화장실(여); InteriorOrExteriorSpace: INTERNAL
Pset_SpaceCommon - Reference: 화장실(여) 312; FloorCovering: 자기질타일(바탕32, 압착8); WallCovering: 도기질타일(200x200x8T); CeilingCovering: 열경화성 천정재 (300x300x1.2T)
BaseQuantities - NetFloorArea: 17.0979 m2; Height: 2710 mm; GrossPerimeter: 17166 mm; GrossFloorArea: 17.0979 m2; GrossVolume: 46.3352 m3
ID 데이터 - 바닥 마감: 자기질타일(바탕32, 압착8); 번호: 312; 베이스 마감: 목재 걸레받이; 벽 마감: 도기질타일(200x200x8T); 이름: 화장실(여); 천장 마감: 열경화성 천정재 (300x300x1.2T)
공정 - 공정: 새 구성
구속조건 - 상한값: 지상 10층; 레벨: 지상 10층; 베이스 간격띄우기: -50 mm; 한계 간격띄우기: 2660 mm
기타 - 공정 ID: 0; 카테고리: 룸; 거실여부: yes; 공간분류코드: 33234; 실ID: 1008
에너지 해석 - 구역별 실제 전력 부하: 0; 구역별 실제 조명 부하: 0; 기초 전력 부하: 공간 유형별; 기초 조명 부하: 공간 유형별; 사람 수: 0; 열 부하 값: 공간 유형별; 전력 부하 단위: 전력 밀도; 조명 부하 단위: 전력 밀도; 1인당 잠열 취득: 58.6142 W; 1인당 현열 취득: 73.2678 W; 개인별 면적: 28.5714 m2; 실제 전력 부하: 0 W; 실제 조명 부하: 0 W; 지정된 구역별 전력 부하: 13.9931; 지정된 구역별 조명 부하: 10.7639; 지정된 전력 부하: 0 W; 지정된 조명 부하: 0 W; 천장속 조명 방사: 20; 총 개인별 열 취득: 131.882 W
치수 - 계산 높이: 1000 mm; 둘레: 17166 mm; 면적: 17.0979 m2; 무한한 높이: 2710 mm; 체적: 44.1125 m3

# IfcSpace: 휀룸/창고 129:3690418, 129
In: 지하2층
LongName: 휀룸/창고; InteriorOrExteriorSpace: INTERNAL
Pset_SpaceCommon - Reference: 휀룸/창고 129; FloorCovering: 우레탄페인트; WallCovering: 수성페인트; CeilingCovering: 수성페인트 2회
BaseQuantities - NetFloorArea: 12.5881 m2; Height: 4000 mm; GrossPerimeter: 19622.4 mm; GrossFloorArea: 12.5881 m2; GrossVolume: 50.3522 m3
ID 데이터 - 바닥 마감: 우레탄페인트; 번호: 129; 베이스 마감: 목재 걸레받이; 벽 마감: 수성페인트; 이름: 휀룸/창고; 천장 마감: 수성페인트 2회
공정 - 공정: 새 구성
구속조건 - 베이스 간격띄우기: 0 mm; 상한값: 지하2층; 레벨: 지하2층; 한계 간격띄우기: 4000 mm
기타 - 거실여부: no; 공정 ID: 0; 카테고리: 룸; 공간분류코드: 33227; 실ID: B205
에너지 해석 - 구역별 실제 전력 부하: 0; 구역별 실제 조명 부하: 0; 기초 전력 부하: 공간 유형별; 기초 조명 부하: 공간 유형별; 사람 수: 0; 열 부하 값: 공간 유형별; 전력 부하 단위: 전력 밀도; 조명 부하 단위: 전력 밀도; 1인당 잠열 취득: 58.6142 W; 1인당 현열 취득: 73.2678 W; 개인별 면적: 28.5714 m2; 실제 전력 부하: 0 W; 실제 조명 부하: 0 W; 지정된 구역별 전력 부하: 13.9931; 지정된 구역별 조명 부하: 10.7639; 지정된 전력 부하: 0 W; 지정된 조명 부하: 0 W; 천장속 조명 방사: 20; 총 개인별 열 취득: 131.882 W
치수 - 계산 높이: 0 mm; 둘레: 19353.7 mm; 면적: 12.5881 m2; 무한한 높이: 4000 mm; 체적: 50.3524 m3

# IfcSpace: 휀룸/창고 130:3690429, 130
In: 지하2층
LongName: 휀룸/창고; InteriorOrExteriorSpace: INTERNAL
Pset_SpaceCommon - Reference: 휀룸/창고 130; FloorCovering: 우레탄페인트; WallCovering: 수성페인트; CeilingCovering: 수성페인트 2회
BaseQuantities - NetFloorArea: 9.8415 m2; Height: 5800 mm; GrossPerimeter: 12690 mm; GrossFloorArea: 9.8415 m2; GrossVolume: 57.0807 m3
ID 데이터 - 바닥 마감: 우레탄페인트; 번호: 130; 베이스 마감: 목재 걸레받이; 벽 마감: 수성페인트; 이름: 휀룸/창고; 천장 마감: 수성페인트 2회
공정 - 공정: 새 구성
구속조건 - 상한값: 지하2층; 레벨: 지하2층; 베이스 간격띄우기: -1800 mm; 한계 간격띄우기: 4000 mm
기타 - 거실여부: no; 공정 ID: 0; 카테고리: 룸; 공간분류코드: 33227; 실ID: B206
에너지 해석 - 구역별 실제 전력 부하: 0; 구역별 실제 조명 부하: 0; 기초 전력 부하: 공간 유형별; 기초 조명 부하: 공간 유형별; 사람 수: 0; 열 부하 값: 공간 유형별; 전력 부하 단위: 전력 밀도; 조명 부하 단위: 전력 밀도; 1인당 잠열 취득: 58.6142 W; 1인당 현열 취득: 73.2678 W; 개인별 면적: 28.5714 m2; 실제 전력 부하: 0 W; 실제 조명 부하: 0 W; 지정된 구역별 전력 부하: 13.9931; 지정된 구역별 조명 부하: 10.7639; 지정된 전력 부하: 0 W; 지정된 조명 부하: 0 W; 천장속 조명 방사: 20; 총 개인별 열 취득: 131.882 W
치수 - 계산 높이: 0 mm; 둘레: 12690 mm; 면적: 9.8415 m2; 무한한 높이: 5800 mm; 체적: 55.1124 m3

# IfcSpace: 휀룸/창고 131:3690432, 131
In: 지하2층
LongName: 휀룸/창고; InteriorOrExteriorSpace: INTERNAL
Pset_SpaceCommon - Reference: 휀룸/창고 131; FloorCovering: 우레탄페인트; WallCovering: 수성페인트; CeilingCovering: 수성페인트 2회
BaseQuantities - NetFloorArea: 4.4685 m2; Height: 5800 mm; GrossFloorArea: 4.4685 m2; GrossVolume: 25.9173 m3
ID 데이터 - 바닥 마감: 우레탄페인트; 번호: 131; 베이스 마감: 목재 걸레받이; 벽 마감: 수성페인트; 이름: 휀룸/창고; 천장 마감: 수성페인트 2회
공정 - 공정: 새 구성
구속조건 - 상한값: 지하2층; 레벨: 지하2층; 베이스 간격띄우기: -1800 mm; 한계 간격띄우기: 4000 mm
기타 - 거실여부: no; 공정 ID: 0; 카테고리: 룸; 공간분류코드: 33227; 실ID: B207
에너지 해석 - 구역별 실제 전력 부하: 0; 구역별 실제 조명 부하: 0; 기초 전력 부하: 공간 유형별; 기초 조명 부하: 공간 유형별; 사람 수: 0; 열 부하 값: 공간 유형별; 전력 부하 단위: 전력 밀도; 조명 부하 단위: 전력 밀도; 1인당 잠열 취득: 58.6142 W; 1인당 현열 취득: 73.2678 W; 개인별 면적: 28.5714 m2; 실제 전력 부하: 0 W; 실제 조명 부하: 0 W; 지정된 구역별 전력 부하: 13.9931; 지정된 구역별 조명 부하: 10.7639; 지정된 전력 부하: 0 W; 지정된 조명 부하: 0 W; 천장속 조명 방사: 20; 총 개인별 열 취득: 131.882 W
치수 - 계산 높이: 0 mm; 둘레: 8710 mm; 면적: 4.4685 m2; 무한한 높이: 5800 mm; 체적: 25.0236 m3

# IfcSpace: 휀룸/창고 137:3691072, 137
In: 지하1층
LongName: 휀룸/창고; InteriorOrExteriorSpace: INTERNAL
Pset_SpaceCommon - Reference: 휀룸/창고 137; FloorCovering: 우레탄페인트; WallCovering: 수성페인트; CeilingCovering: 수성페인트 2회
BaseQuantities - NetFloorArea: 14.85 m2; Height: 5900 mm; GrossFloorArea: 14.85 m2; GrossVolume: 87.615 m3
ID 데이터 - 바닥 마감: 우레탄페인트; 번호: 137; 베이스 마감: 목재 걸레받이; 벽 마감: 수성페인트; 이름: 휀룸/창고; 천장 마감: 수성페인트 2회
공정 - 공정: 새 구성
구속조건 - 베이스 간격띄우기: 0 mm; 상한값: 지하1층; 레벨: 지하1층; 한계 간격띄우기: 5900 mm
기타 - 거실여부: no; 공정 ID: 0; 카테고리: 룸; 공간분류코드: 33227; 실ID: B102
에너지 해석 - 구역별 실제 전력 부하: 0; 구역별 실제 조명 부하: 0; 기초 전력 부하: 공간 유형별; 기초 조명 부하: 공간 유형별; 사람 수: 0; 열 부하 값: 공간 유형별; 전력 부하 단위: 전력 밀도; 조명 부하 단위: 전력 밀도; 1인당 잠열 취득: 58.6142 W; 1인당 현열 취득: 73.2678 W; 개인별 면적: 28.5714 m2; 실제 전력 부하: 0 W; 실제 조명 부하: 0 W; 지정된 구역별 전력 부하: 13.9931; 지정된 구역별 조명 부하: 10.7639; 지정된 전력 부하: 0 W; 지정된 조명 부하: 0 W; 천장속 조명 방사: 20; 총 개인별 열 취득: 131.882 W
치수 - 계산 높이: 0 mm; 둘레: 16400 mm; 면적: 14.85 m2; 무한한 높이: 5900 mm; 체적: 78.705 m3

# IfcSpace: 휀룸/창고 146:3691189, 146
In: 지하1층
LongName: 휀룸/창고; InteriorOrExteriorSpace: INTERNAL
Pset_SpaceCommon - Reference: 휀룸/창고 146; FloorCovering: 우레탄페인트; WallCovering: 수성페인트; CeilingCovering: 수성페인트 2회
BaseQuantities - NetFloorArea: 3.97926 m2; Height: 5900 mm; GrossPerimeter: 10245.3 mm; GrossFloorArea: 3.97926 m2; GrossVolume: 23.4777 m3
ID 데이터 - 바닥 마감: 우레탄페인트; 번호: 146; 베이스 마감: 목재 걸레받이; 벽 마감: 수성페인트; 이름: 휀룸/창고; 천장 마감: 수성페인트 2회
공정 - 공정: 새 구성
구속조건 - 베이스 간격띄우기: 0 mm; 상한값: 지하1층; 레벨: 지하1층; 한계 간격띄우기: 5900 mm
기타 - 거실여부: no; 공정 ID: 0; 카테고리: 룸; 공간분류코드: 33227; 실ID: B109
에너지 해석 - 구역별 실제 전력 부하: 0; 구역별 실제 조명 부하: 0; 기초 전력 부하: 공간 유형별; 기초 조명 부하: 공간 유형별; 사람 수: 0; 열 부하 값: 공간 유형별; 전력 부하 단위: 전력 밀도; 조명 부하 단위: 전력 밀도; 1인당 잠열 취득: 58.6142 W; 1인당 현열 취득: 73.2678 W; 개인별 면적: 28.5714 m2; 실제 전력 부하: 0 W; 실제 조명 부하: 0 W; 지정된 구역별 전력 부하: 13.9931; 지정된 구역별 조명 부하: 10.7639; 지정된 전력 부하: 0 W; 지정된 조명 부하: 0 W; 천장속 조명 방사: 20; 총 개인별 열 취득: 131.882 W
치수 - 계산 높이: 0 mm; 둘레: 10006.8 mm; 면적: 3.97926 m2; 무한한 높이: 5900 mm; 체적: 23.4776 m3

# IfcSpace: 휀룸/창고 147:3691192, 147
In: 지하1층
LongName: 휀룸/창고; InteriorOrExteriorSpace: INTERNAL
Pset_SpaceCommon - Reference: 휀룸/창고 147; FloorCovering: 우레탄페인트; WallCovering: 수성페인트; CeilingCovering: 수성페인트 2회
BaseQuantities - NetFloorArea: 8.63481 m2; Height: 5900 mm; GrossPerimeter: 15179.8 mm; GrossFloorArea: 8.63481 m2; GrossVolume: 50.9454 m3
ID 데이터 - 바닥 마감: 우레탄페인트; 번호: 147; 베이스 마감: 목재 걸레받이; 벽 마감: 수성페인트; 이름: 휀룸/창고; 천장 마감: 수성페인트 2회
공정 - 공정: 새 구성
구속조건 - 베이스 간격띄우기: 0 mm; 상한값: 지하1층; 레벨: 지하1층; 한계 간격띄우기: 5900 mm
기타 - 거실여부: no; 공정 ID: 0; 카테고리: 룸; 공간분류코드: 33227; 실ID: B110
에너지 해석 - 구역별 실제 전력 부하: 0; 구역별 실제 조명 부하: 0; 기초 전력 부하: 공간 유형별; 기초 조명 부하: 공간 유형별; 사람 수: 0; 열 부하 값: 공간 유형별; 전력 부하 단위: 전력 밀도; 조명 부하 단위: 전력 밀도; 1인당 잠열 취득: 58.6142 W; 1인당 현열 취득: 73.2678 W; 개인별 면적: 28.5714 m2; 실제 전력 부하: 0 W; 실제 조명 부하: 0 W; 지정된 구역별 전력 부하: 13.9931; 지정된 구역별 조명 부하: 10.7639; 지정된 전력 부하: 0 W; 지정된 조명 부하: 0 W; 천장속 조명 방사: 20; 총 개인별 열 취득: 131.882 W
치수 - 계산 높이: 0 mm; 둘레: 15101.5 mm; 면적: 8.63481 m2; 무한한 높이: 5900 mm; 체적: 50.9453 m3

# IfcSpace: 휴게실 173:3691304, 173
In: 지상 2층
LongName: 휴게실; InteriorOrExteriorSpace: INTERNAL
Pset_SpaceCommon - Reference: 휴게실 173; FloorCovering: T32 테라조타일; WallCovering: 수성페인트; CeilingCovering: T6무석면택스마감
BaseQuantities - NetFloorArea: 75.6448 m2; Height: 3180 mm; GrossPerimeter: 42026 mm; GrossFloorArea: 75.6448 m2; GrossVolume: 240.55 m3
ID 데이터 - 바닥 마감: T32 테라조타일; 번호: 173; 베이스 마감: PVC 걸레받이; 벽 마감: 수성페인트; 이름: 휴게실; 천장 마감: T6무석면택스마감
공정 - 공정: 새 구성
구속조건 - 베이스 간격띄우기: 0 mm; 레벨: 지상 2층; 상한값: 지상 2층; 한계 간격띄우기: 3180 mm
기타 - 공정 ID: 0; 카테고리: 룸; 거실여부: yes; 방화구획: yes; 공간분류코드: 33235; 실ID: 201
에너지 해석 - 구역별 실제 전력 부하: 0; 구역별 실제 조명 부하: 0; 기초 전력 부하: 공간 유형별; 기초 조명 부하: 공간 유형별; 사람 수: 0; 열 부하 값: 공간 유형별; 전력 부하 단위: 전력 밀도; 조명 부하 단위: 전력 밀도; 1인당 잠열 취득: 58.6142 W; 1인당 현열 취득: 73.2678 W; 개인별 면적: 28.5714 m2; 실제 전력 부하: 0 W; 실제 조명 부하: 0 W; 지정된 구역별 전력 부하: 13.9931; 지정된 구역별 조명 부하: 10.7639; 지정된 전력 부하: 0 W; 지정된 조명 부하: 0 W; 천장속 조명 방사: 20; 총 개인별 열 취득: 131.882 W
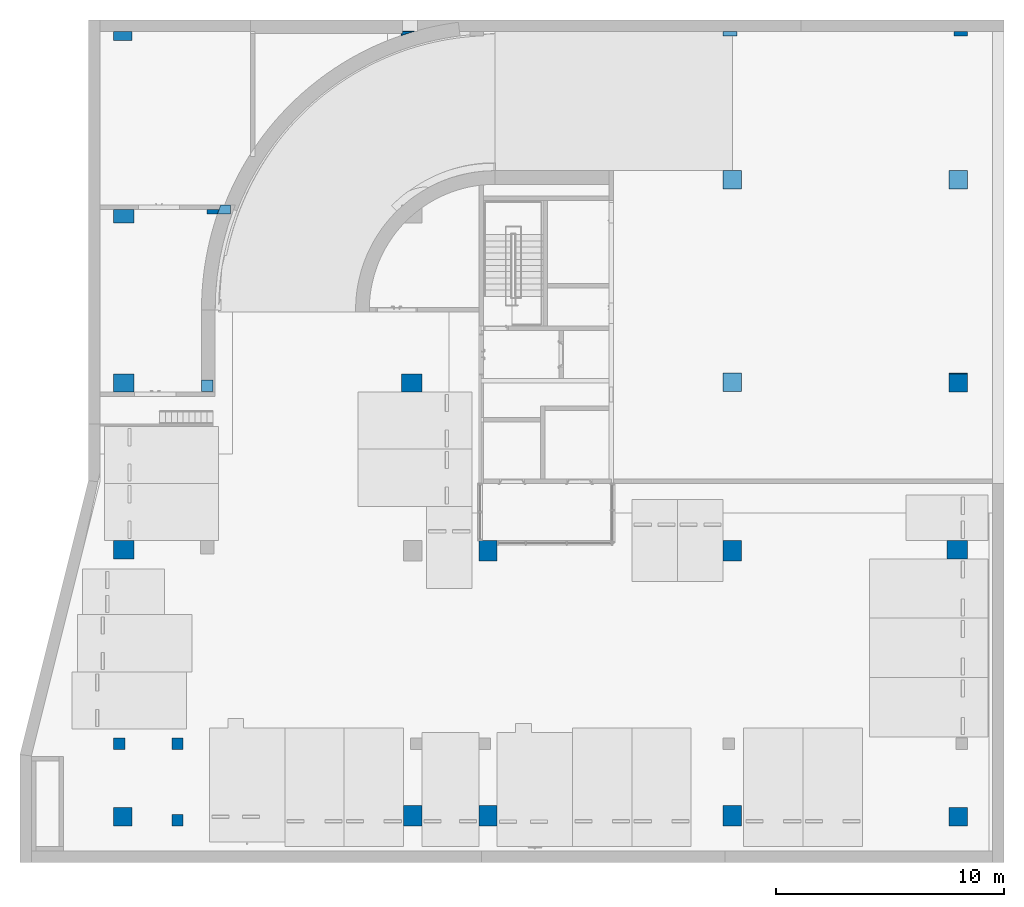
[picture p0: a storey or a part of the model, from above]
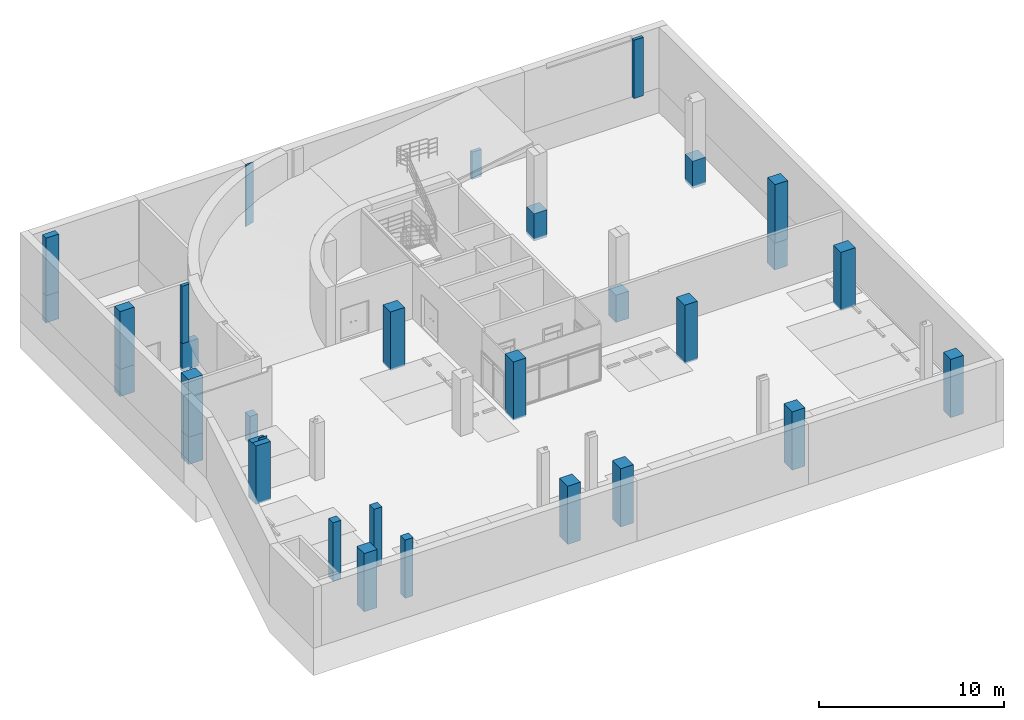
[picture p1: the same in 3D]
Properties of the parts of a building model (IFC2X3), part 6 of 39

# IfcSpace: 휴게실 173:3691304, 173
치수 - 계산 높이: 1000 mm; 둘레: 41828 mm; 면적: 75.6448 m2; 무한한 높이: 3180 mm; 체적: 240.55 m3

# IfcBeam: BM111-철근콘크리트구조 보:BM110-철근 콘크리트구조 보_300 x 1500_1B4(역보) (3)
In: 지상 1층
Type - ID 데이터 - 유형 마크: B4; 유형 이름: BM110-철근 콘크리트구조 보_300 x 1500_1B4(역보)
Type - 구조 - 단면 모양: 0
Type - 기타 - 내화구조여부: yes; 주요구조부여부: yes; 카테고리: 구조 프레임; KBIMS-부위코드: E23; 제작정보: bSK-2021_KBIMS2.0-bC; 조달청표준공사코드: AD; 패밀리 이름: BM111-철근콘크리트구조 보
Type - 재료 및 마감재 - 구조 재료: KBIMS-콘크리트
Type - 치수 - 가로치수: 300 mm; 세로치수: 1500 mm
Type - Pset_BeamCommon - IsExternal: no; LoadBearing: yes
Material: KBIMS-콘크리트
Pset_BeamCommon - Slope: 0 deg; Reference: BM110-철근 콘크리트구조 보_300 x 1500_1B4(역보)
Pset_QuantityTakeOff - Reference: BM110-철근 콘크리트구조 보_300 x 1500_1B4(역보); sets with these values: 2
ID 데이터 - 연관 있음: no
공정 - 생성 공정: 새 구성
구속조건 - 단면형상 회전: 0 deg; 참조 레벨: 지상 1층; 참조 레벨 입면도: 0 mm
구조 - 보강 철근 피복 - 다른 면: 보강 철근 피복 1 <25 mm>; 보강 철근 피복 - 상단 면: 보강 철근 피복 1 <25 mm>; 구조적 용도: 거더
기타 - 패밀리: BM111-철근콘크리트구조 보; 유형: BM110-철근 콘크리트구조 보_300 x 1500_1B4(역보); 유형 ID: 7667212; 패밀리 및 유형: BM111-철근콘크리트구조 보: BM110-철근 콘크리트구조 보_300 x 1500_1B4(역보)
기하학적 위치 - yz 맞춤: 균일; y 간격띄우기 값: 0 mm; y 맞춤: 원점; z 간격띄우기 값: 0 mm; z 맞춤: 하단; 결합 상태: 하나 또는 두 개의 결합 사용 안 함
치수 - 단면적: 0.45 m2
Name (BM111-철근콘크리트구조 보:BM110-철근 콘크리트구조 보_300 x 1500_1B4(역보):...) | CrossSectionArea (m2) | NetVolume (m3) = 체적 (m3) | Span (mm) = 길이 (mm) | 끝 레벨 간격띄우기 (mm) = 시작 레벨 간격띄우기 (mm) = 하단 기준 레벨 (mm) | 보강 철근 피복 - 하단 면 | 절단 길이 (mm) | 상단 기준 레벨 (mm)
7667178 | 12.5506 | 2.47246 | 6485 | -750 | 보강 철근 피복 1 <25 mm> | 6510.4 | 750
7668322 | 9.36743 | 0.668083 | 6485 | -750 | 보강 철근 피복 1 <25 mm> | 6510.4 | 750
7669275 | 0.39 | 2.49811 | 6380 | 300 |  | 6405.4 | 1800

# IfcBeam: BM111-철근콘크리트구조 보:BM110-철근 콘크리트구조 보_300 x 800_1B6 (2)
In: 지상 1층
Type - ID 데이터 - 유형 마크: B6; 유형 이름: BM110-철근 콘크리트구조 보_300 x 800_1B6
Type - 구조 - 단면 모양: 0
Type - 기타 - 내화구조여부: yes; 주요구조부여부: yes; 카테고리: 구조 프레임; KBIMS-부위코드: E23; 제작정보: bSK-2021_KBIMS2.0-bC; 조달청표준공사코드: AD; 패밀리 이름: BM111-철근콘크리트구조 보
Type - 재료 및 마감재 - 구조 재료: KBIMS-콘크리트
Type - 치수 - 가로치수: 300 mm; 세로치수: 800 mm
Type - Pset_BeamCommon - IsExternal: no; LoadBearing: yes
Material: KBIMS-콘크리트
Pset_BeamCommon - Slope: 0 deg; Reference: BM110-철근 콘크리트구조 보_300 x 800_1B6; Span: 2825 mm
Pset_QuantityTakeOff - Reference: BM110-철근 콘크리트구조 보_300 x 800_1B6; sets with these values: 2
ID 데이터 - 연관 있음: no
공정 - 생성 공정: 새 구성
구속조건 - 끝 레벨 간격띄우기: 0 mm; 단면형상 회전: 0 deg; 방향: 보통; 시작 레벨 간격띄우기: 0 mm; 참조 레벨: 지상 1층; 참조 레벨 입면도: 0 mm; 작업 기준면: 레벨 : 지상 1층
구조 - 보강 철근 피복 - 다른 면: 보강 철근 피복 1 <25 mm>; 보강 철근 피복 - 하단 면: 보강 철근 피복 1 <25 mm>; 구조적 용도: 기타; 절단 길이: 2524.72 mm
기타 - 패밀리: BM111-철근콘크리트구조 보; 유형: BM110-철근 콘크리트구조 보_300 x 800_1B6; 유형 ID: 7667214; 패밀리 및 유형: BM111-철근콘크리트구조 보: BM110-철근 콘크리트구조 보_300 x 800_1B6
기하학적 위치 - yz 맞춤: 균일; y 간격띄우기 값: 0 mm; y 맞춤: 원점; z 맞춤: 상단; 결합 상태: 두 결합 모두 사용; z 간격띄우기 값: -600 mm
치수 - 길이: 2825 mm; 단면적: 0.24 m2; 상단 기준 레벨: -600 mm; 하단 기준 레벨: -1400 mm
Name (BM111-철근콘크리트구조 보:BM110-철근 콘크리트구조 보_300 x 800_1B6:...) | CrossSectionArea (m2) | NetVolume (m3) = 체적 (m3)
7667189 | 0.17458 | 0.440765
7668334 | 0.0619322 | 0.156361

# IfcBeam: BM111-철근콘크리트구조 보:BM110-철근 콘크리트구조 보_400 x 400_2-10B1 (27)
Type - ID 데이터 - 유형 마크: B1; 유형 이름: BM110-철근 콘크리트구조 보_400 x 400_2-10B1
Type - 구조 - 단면 모양: 0
Type - 기타 - 내화구조여부: yes; 주요구조부여부: yes; 카테고리: 구조 프레임; KBIMS-부위코드: E23; 제작정보: bSK-2021_KBIMS2.0-bC; 조달청표준공사코드: AD; 패밀리 이름: BM111-철근콘크리트구조 보
Type - 재료 및 마감재 - 구조 재료: KBIMS-콘크리트
Type - 치수 - 가로치수: 400 mm; 세로치수: 400 mm
Type - Pset_BeamCommon - IsExternal: no; LoadBearing: yes
Material: KBIMS-콘크리트
BaseQuantities - CrossSectionArea: 0.1 m2
Pset_BeamCommon - Slope: 0 deg; Reference: BM110-철근 콘크리트구조 보_400 x 400_2-10B1
Pset_QuantityTakeOff - Reference: BM110-철근 콘크리트구조 보_400 x 400_2-10B1; sets with these values: 2
ID 데이터 - 연관 있음: no
공정 - 생성 공정: 새 구성
구속조건 - 끝 레벨 간격띄우기: 0 mm; 단면형상 회전: 0 deg; 방향: 보통; 시작 레벨 간격띄우기: 0 mm
구조 - 보강 철근 피복 - 다른 면: 보강 철근 피복 1 <25 mm>; 보강 철근 피복 - 하단 면: 보강 철근 피복 1 <25 mm>; 구조적 용도: 기타
기타 - 패밀리: BM111-철근콘크리트구조 보; 유형: BM110-철근 콘크리트구조 보_400 x 400_2-10B1; 유형 ID: 7669421; 패밀리 및 유형: BM111-철근콘크리트구조 보: BM110-철근 콘크리트구조 보_400 x 400_2-10B1
기하학적 위치 - yz 맞춤: 균일; y 간격띄우기 값: 0 mm; y 맞춤: 원점; z 간격띄우기 값: 0 mm; z 맞춤: 상단; 결합 상태: 두 결합 모두 사용
치수 - 단면적: 0.16 m2
Name (BM111-철근콘크리트구조 보:BM110-철근 콘크리트구조 보_400 x 400_2-10B1:...) | In | NetVolume (m3) = 체적 (m3) | Span (mm) = 길이 (mm) | 참조 레벨 | 작업 기준면 | 참조 레벨 입면도 (mm) = 상단 기준 레벨 (mm) | 절단 길이 (mm) | 하단 기준 레벨 (mm)
7668363 | 지상 2층 | 0.99 | 10300 | 지상 2층 | 레벨 : 지상 2층 | 4800 | 9900 | 4400
7668369 | 지상 2층 | 0.969998 | 10200 | 지상 2층 | 레벨 : 지상 2층 | 4800 | 9699.98 | 4400
7668370 | 지상 2층 | 0.969998 | 10200 | 지상 2층 | 레벨 : 지상 2층 | 4800 | 9699.98 | 4400
7668421 | 지상 3층 | 0.99 | 10300 | 지상 3층 | 레벨 : 지상 3층 | 9300 | 9900 | 8900
7668427 | 지상 3층 | 0.969998 | 10200 | 지상 3층 | 레벨 : 지상 3층 | 9300 | 9699.98 | 8900
7668428 | 지상 3층 | 0.969998 | 10200 | 지상 3층 | 레벨 : 지상 3층 | 9300 | 9699.98 | 8900
7668668 | 지상 4층 | 0.99 | 10300 | 지상 4층 | 레벨 : 지상 4층 | 13400 | 9900 | 13000
7668674 | 지상 4층 | 0.969998 | 10200 | 지상 4층 | 레벨 : 지상 4층 | 13400 | 9699.98 | 13000
7668675 | 지상 4층 | 0.969998 | 10200 | 지상 4층 | 레벨 : 지상 4층 | 13400 | 9699.98 | 13000
7668726 | 지상 5층 | 0.99 | 10300 | 지상 5층 | 레벨 : 지상 5층 | 17500 | 9900 | 17100
7668732 | 지상 5층 | 0.969998 | 10200 | 지상 5층 | 레벨 : 지상 5층 | 17500 | 9699.98 | 17100
7668733 | 지상 5층 | 0.969998 | 10200 | 지상 5층 | 레벨 : 지상 5층 | 17500 | 9699.98 | 17100
7668784 | 지상 6층 | 0.99 | 10300 | 지상 6층 | 레벨 : 지상 6층 | 21600 | 9900 | 21200
7668790 | 지상 6층 | 0.969998 | 10200 | 지상 6층 | 레벨 : 지상 6층 | 21600 | 9699.98 | 21200
7668791 | 지상 6층 | 0.969998 | 10200 | 지상 6층 | 레벨 : 지상 6층 | 21600 | 9699.98 | 21200
7668842 | 지상 7층 | 0.99 | 10300 | 지상 7층 | 레벨 : 지상 7층 | 25700 | 9900 | 25300
7668848 | 지상 7층 | 0.969998 | 10200 | 지상 7층 | 레벨 : 지상 7층 | 25700 | 9699.98 | 25300
7668849 | 지상 7층 | 0.969998 | 10200 | 지상 7층 | 레벨 : 지상 7층 | 25700 | 9699.98 | 25300
7668900 | 지상 8층 | 0.99 | 10300 | 지상 8층 | 레벨 : 지상 8층 | 29800 | 9900 | 29400
7668906 | 지상 8층 | 0.969998 | 10200 | 지상 8층 | 레벨 : 지상 8층 | 29800 | 9699.98 | 29400
7668907 | 지상 8층 | 0.969998 | 10200 | 지상 8층 | 레벨 : 지상 8층 | 29800 | 9699.98 | 29400
7668958 | 지상 9층 | 0.99 | 10300 | 지상 9층 | 레벨 : 지상 9층 | 33900 | 9900 | 33500
7668964 | 지상 9층 | 0.969998 | 10200 | 지상 9층 | 레벨 : 지상 9층 | 33900 | 9699.98 | 33500
7668965 | 지상 9층 | 0.969998 | 10200 | 지상 9층 | 레벨 : 지상 9층 | 33900 | 9699.98 | 33500
7669016 | 지상 10층 | 0.99 | 10300 | 지상 10층 | 레벨 : 지상 10층 | 38400 | 9900 | 38000
7669022 | 지상 10층 | 0.969998 | 10200 | 지상 10층 | 레벨 : 지상 10층 | 38400 | 9699.98 | 38000
7669023 | 지상 10층 | 0.969998 | 10200 | 지상 10층 | 레벨 : 지상 10층 | 38400 | 9699.98 | 38000

# IfcBeam: BM111-철근콘크리트구조 보:BM110-철근 콘크리트구조 보_400 x 400_2-10B2 (36)
Type - ID 데이터 - 유형 마크: B2; 유형 이름: BM110-철근 콘크리트구조 보_400 x 400_2-10B2
Type - 구조 - 단면 모양: 0
Type - 기타 - 내화구조여부: yes; 주요구조부여부: yes; 카테고리: 구조 프레임; KBIMS-부위코드: E23; 제작정보: bSK-2021_KBIMS2.0-bC; 조달청표준공사코드: AD; 패밀리 이름: BM111-철근콘크리트구조 보
Type - 재료 및 마감재 - 구조 재료: KBIMS-콘크리트
Type - 치수 - 가로치수: 400 mm; 세로치수: 400 mm
Type - Pset_BeamCommon - IsExternal: no; LoadBearing: yes
Material: KBIMS-콘크리트
BaseQuantities - CrossSectionArea: 0.1 m2
Pset_BeamCommon - Slope: 0 deg; Reference: BM110-철근 콘크리트구조 보_400 x 400_2-10B2
Pset_QuantityTakeOff - Reference: BM110-철근 콘크리트구조 보_400 x 400_2-10B2; sets with these values: 2
ID 데이터 - 연관 있음: no
공정 - 생성 공정: 새 구성
구속조건 - 끝 레벨 간격띄우기: 0 mm; 단면형상 회전: 0 deg; 방향: 보통; 시작 레벨 간격띄우기: 0 mm
구조 - 보강 철근 피복 - 다른 면: 보강 철근 피복 1 <25 mm>; 보강 철근 피복 - 하단 면: 보강 철근 피복 1 <25 mm>; 구조적 용도: 거더
기타 - 패밀리: BM111-철근콘크리트구조 보; 유형: BM110-철근 콘크리트구조 보_400 x 400_2-10B2; 유형 ID: 7669427; 패밀리 및 유형: BM111-철근콘크리트구조 보: BM110-철근 콘크리트구조 보_400 x 400_2-10B2
기하학적 위치 - yz 맞춤: 균일; y 간격띄우기 값: 0 mm; y 맞춤: 원점; z 간격띄우기 값: 0 mm; z 맞춤: 상단; 결합 상태: 두 결합 모두 사용
치수 - 단면적: 0.16 m2
Name (BM111-철근콘크리트구조 보:BM110-철근 콘크리트구조 보_400 x 400_2-10B2:...) | In | NetVolume (m3) = 체적 (m3) | Span (mm) = 길이 (mm) | 참조 레벨 | 작업 기준면 | 참조 레벨 입면도 (mm) = 상단 기준 레벨 (mm) | 절단 길이 (mm) | 하단 기준 레벨 (mm)
7668353 | 지상 2층 | 1.15 | 12000 | 지상 2층 | 레벨 : 지상 2층 | 4800 | 11500 | 4400
7668354 | 지상 2층 | 1.15 | 12000 | 지상 2층 | 레벨 : 지상 2층 | 4800 | 11500 | 4400
7668356 | 지상 2층 | 1.15 | 12000 | 지상 2층 | 레벨 : 지상 2층 | 4800 | 11500 | 4400
7668357 | 지상 2층 | 1.15 | 12000 | 지상 2층 | 레벨 : 지상 2층 | 4800 | 11500 | 4400
7668411 | 지상 3층 | 1.15 | 12000 | 지상 3층 | 레벨 : 지상 3층 | 9300 | 11500 | 8900
7668412 | 지상 3층 | 1.15 | 12000 | 지상 3층 | 레벨 : 지상 3층 | 9300 | 11500 | 8900
7668414 | 지상 3층 | 1.15 | 12000 | 지상 3층 | 레벨 : 지상 3층 | 9300 | 11500 | 8900
7668415 | 지상 3층 | 1.15 | 12000 | 지상 3층 | 레벨 : 지상 3층 | 9300 | 11500 | 8900
7668658 | 지상 4층 | 1.15 | 12000 | 지상 4층 | 레벨 : 지상 4층 | 13400 | 11500 | 13000
7668659 | 지상 4층 | 1.15 | 12000 | 지상 4층 | 레벨 : 지상 4층 | 13400 | 11500 | 13000
7668661 | 지상 4층 | 1.15 | 12000 | 지상 4층 | 레벨 : 지상 4층 | 13400 | 11500 | 13000
7668662 | 지상 4층 | 1.15 | 12000 | 지상 4층 | 레벨 : 지상 4층 | 13400 | 11500 | 13000
7668716 | 지상 5층 | 1.15 | 12000 | 지상 5층 | 레벨 : 지상 5층 | 17500 | 11500 | 17100
7668717 | 지상 5층 | 1.15 | 12000 | 지상 5층 | 레벨 : 지상 5층 | 17500 | 11500 | 17100
7668719 | 지상 5층 | 1.15 | 12000 | 지상 5층 | 레벨 : 지상 5층 | 17500 | 11500 | 17100
7668720 | 지상 5층 | 1.15 | 12000 | 지상 5층 | 레벨 : 지상 5층 | 17500 | 11500 | 17100
7668774 | 지상 6층 | 1.15 | 12000 | 지상 6층 | 레벨 : 지상 6층 | 21600 | 11500 | 21200
7668775 | 지상 6층 | 1.15 | 12000 | 지상 6층 | 레벨 : 지상 6층 | 21600 | 11500 | 21200
7668777 | 지상 6층 | 1.155 | 12050 | 지상 6층 | 레벨 : 지상 6층 | 21600 | 11550 | 21200
7668778 | 지상 6층 | 1.155 | 12050 | 지상 6층 | 레벨 : 지상 6층 | 21600 | 11550 | 21200
7668832 | 지상 7층 | 1.15 | 12000 | 지상 7층 | 레벨 : 지상 7층 | 25700 | 11500 | 25300
7668833 | 지상 7층 | 1.15 | 12000 | 지상 7층 | 레벨 : 지상 7층 | 25700 | 11500 | 25300
7668835 | 지상 7층 | 1.155 | 12050 | 지상 7층 | 레벨 : 지상 7층 | 25700 | 11550 | 25300
7668836 | 지상 7층 | 1.155 | 12050 | 지상 7층 | 레벨 : 지상 7층 | 25700 | 11550 | 25300
7668890 | 지상 8층 | 1.15 | 12000 | 지상 8층 | 레벨 : 지상 8층 | 29800 | 11500 | 29400
7668891 | 지상 8층 | 1.15 | 12000 | 지상 8층 | 레벨 : 지상 8층 | 29800 | 11500 | 29400
7668893 | 지상 8층 | 1.155 | 12050 | 지상 8층 | 레벨 : 지상 8층 | 29800 | 11550 | 29400
7668894 | 지상 8층 | 1.155 | 12050 | 지상 8층 | 레벨 : 지상 8층 | 29800 | 11550 | 29400
7668948 | 지상 9층 | 1.15 | 12000 | 지상 9층 | 레벨 : 지상 9층 | 33900 | 11500 | 33500
7668949 | 지상 9층 | 1.15 | 12000 | 지상 9층 | 레벨 : 지상 9층 | 33900 | 11500 | 33500
7668951 | 지상 9층 | 1.155 | 12050 | 지상 9층 | 레벨 : 지상 9층 | 33900 | 11550 | 33500
7668952 | 지상 9층 | 1.155 | 12050 | 지상 9층 | 레벨 : 지상 9층 | 33900 | 11550 | 33500
7669006 | 지상 10층 | 1.15 | 12000 | 지상 10층 | 레벨 : 지상 10층 | 38400 | 11500 | 38000
7669007 | 지상 10층 | 1.15 | 12000 | 지상 10층 | 레벨 : 지상 10층 | 38400 | 11500 | 38000
7669009 | 지상 10층 | 1.155 | 12050 | 지상 10층 | 레벨 : 지상 10층 | 38400 | 11550 | 38000
7669010 | 지상 10층 | 1.155 | 12050 | 지상 10층 | 레벨 : 지상 10층 | 38400 | 11550 | 38000

# IfcBeam: BM111-철근콘크리트구조 보:BM110-철근 콘크리트구조 보_400 x 400_2-10B3 (72)
Type - ID 데이터 - 유형 마크: B3; 유형 이름: BM110-철근 콘크리트구조 보_400 x 400_2-10B3
Type - 구조 - 단면 모양: 0
Type - 기타 - 내화구조여부: yes; 주요구조부여부: yes; 카테고리: 구조 프레임; KBIMS-부위코드: E23; 제작정보: bSK-2021_KBIMS2.0-bC; 조달청표준공사코드: AD; 패밀리 이름: BM111-철근콘크리트구조 보
Type - 재료 및 마감재 - 구조 재료: KBIMS-콘크리트
Type - 치수 - 가로치수: 400 mm; 세로치수: 400 mm
Type - Pset_BeamCommon - IsExternal: no; LoadBearing: yes
Material: KBIMS-콘크리트
BaseQuantities - CrossSectionArea: 0.1 m2
Pset_BeamCommon - Slope: 0 deg; Reference: BM110-철근 콘크리트구조 보_400 x 400_2-10B3
Pset_QuantityTakeOff - Reference: BM110-철근 콘크리트구조 보_400 x 400_2-10B3; sets with these values: 2
ID 데이터 - 연관 있음: no
공정 - 생성 공정: 새 구성
구속조건 - 끝 레벨 간격띄우기: 0 mm; 단면형상 회전: 0 deg; 방향: 보통; 시작 레벨 간격띄우기: 0 mm
구조 - 보강 철근 피복 - 다른 면: 보강 철근 피복 1 <25 mm>; 보강 철근 피복 - 하단 면: 보강 철근 피복 1 <25 mm>; 구조적 용도: 기타
기타 - 패밀리: BM111-철근콘크리트구조 보; 유형: BM110-철근 콘크리트구조 보_400 x 400_2-10B3; 유형 ID: 7669417; 패밀리 및 유형: BM111-철근콘크리트구조 보: BM110-철근 콘크리트구조 보_400 x 400_2-10B3
기하학적 위치 - yz 맞춤: 균일; y 간격띄우기 값: 0 mm; y 맞춤: 원점; z 간격띄우기 값: 0 mm; z 맞춤: 상단; 결합 상태: 두 결합 모두 사용
치수 - 단면적: 0.16 m2
Name (BM111-철근콘크리트구조 보:BM110-철근 콘크리트구조 보_400 x 400_2-10B3:...) | In | NetVolume (m3) = 체적 (m3) | Span (mm) = 길이 (mm) | 참조 레벨 | 작업 기준면 | 참조 레벨 입면도 (mm) = 상단 기준 레벨 (mm) | 절단 길이 (mm) | 하단 기준 레벨 (mm)
7668342 | 지상 2층 | 1.23 | 12900 | 지상 2층 | 레벨 : 지상 2층 | 4800 | 12300 | 4400
7668364 | 지상 2층 | 1.25 | 13000 | 지상 2층 | 레벨 : 지상 2층 | 4800 | 12500 | 4400
7668373 | 지상 2층 | 1.26001 | 13000 | 지상 2층 | 레벨 : 지상 2층 | 4800 | 12600.1 | 4400
7668374 | 지상 2층 | 1.26001 | 13000 | 지상 2층 | 레벨 : 지상 2층 | 4800 | 12600.1 | 4400
7668389 | 지상 2층 | 1.23 | 12900 | 지상 2층 | 레벨 : 지상 2층 | 4800 | 12300 | 4400
7668390 | 지상 2층 | 1.23 | 12900 | 지상 2층 | 레벨 : 지상 2층 | 4800 | 12300 | 4400
7668391 | 지상 2층 | 1.26001 | 13000 | 지상 2층 | 레벨 : 지상 2층 | 4800 | 12600.1 | 4400
7668392 | 지상 2층 | 1.26001 | 13000 | 지상 2층 | 레벨 : 지상 2층 | 4800 | 12600.1 | 4400
7668400 | 지상 3층 | 1.23 | 12900 | 지상 3층 | 레벨 : 지상 3층 | 9300 | 12300 | 8900
7668422 | 지상 3층 | 1.25 | 13000 | 지상 3층 | 레벨 : 지상 3층 | 9300 | 12500 | 8900
7668431 | 지상 3층 | 1.26501 | 13050 | 지상 3층 | 레벨 : 지상 3층 | 9300 | 12650.1 | 8900
7668432 | 지상 3층 | 1.26001 | 13000 | 지상 3층 | 레벨 : 지상 3층 | 9300 | 12600.1 | 8900
7668447 | 지상 3층 | 1.23 | 12900 | 지상 3층 | 레벨 : 지상 3층 | 9300 | 12300 | 8900
7668448 | 지상 3층 | 1.23 | 12900 | 지상 3층 | 레벨 : 지상 3층 | 9300 | 12300 | 8900
7668449 | 지상 3층 | 1.26001 | 13000 | 지상 3층 | 레벨 : 지상 3층 | 9300 | 12600.1 | 8900
7668450 | 지상 3층 | 1.26501 | 13050 | 지상 3층 | 레벨 : 지상 3층 | 9300 | 12650.1 | 8900
7668647 | 지상 4층 | 1.23 | 12900 | 지상 4층 | 레벨 : 지상 4층 | 13400 | 12300 | 13000
7668669 | 지상 4층 | 1.25 | 13000 | 지상 4층 | 레벨 : 지상 4층 | 13400 | 12500 | 13000
7668678 | 지상 4층 | 1.26001 | 13000 | 지상 4층 | 레벨 : 지상 4층 | 13400 | 12600.1 | 13000
7668679 | 지상 4층 | 1.26001 | 13000 | 지상 4층 | 레벨 : 지상 4층 | 13400 | 12600.1 | 13000
7668694 | 지상 4층 | 1.23 | 12900 | 지상 4층 | 레벨 : 지상 4층 | 13400 | 12300 | 13000
7668695 | 지상 4층 | 1.23 | 12900 | 지상 4층 | 레벨 : 지상 4층 | 13400 | 12300 | 13000
7668696 | 지상 4층 | 1.26001 | 13000 | 지상 4층 | 레벨 : 지상 4층 | 13400 | 12600.1 | 13000
7668697 | 지상 4층 | 1.26001 | 13000 | 지상 4층 | 레벨 : 지상 4층 | 13400 | 12600.1 | 13000
7668705 | 지상 5층 | 1.23 | 12900 | 지상 5층 | 레벨 : 지상 5층 | 17500 | 12300 | 17100
7668727 | 지상 5층 | 1.25 | 13000 | 지상 5층 | 레벨 : 지상 5층 | 17500 | 12500 | 17100
7668736 | 지상 5층 | 1.26001 | 13000 | 지상 5층 | 레벨 : 지상 5층 | 17500 | 12600.1 | 17100
7668737 | 지상 5층 | 1.26001 | 13000 | 지상 5층 | 레벨 : 지상 5층 | 17500 | 12600.1 | 17100
7668752 | 지상 5층 | 1.23 | 12900 | 지상 5층 | 레벨 : 지상 5층 | 17500 | 12300 | 17100
7668753 | 지상 5층 | 1.23 | 12900 | 지상 5층 | 레벨 : 지상 5층 | 17500 | 12300 | 17100
7668754 | 지상 5층 | 1.26001 | 13000 | 지상 5층 | 레벨 : 지상 5층 | 17500 | 12600.1 | 17100
7668755 | 지상 5층 | 1.26001 | 13000 | 지상 5층 | 레벨 : 지상 5층 | 17500 | 12600.1 | 17100
7668763 | 지상 6층 | 1.23 | 12900 | 지상 6층 | 레벨 : 지상 6층 | 21600 | 12300 | 21200
7668785 | 지상 6층 | 1.25 | 13000 | 지상 6층 | 레벨 : 지상 6층 | 21600 | 12500 | 21200
7668794 | 지상 6층 | 1.26001 | 13000 | 지상 6층 | 레벨 : 지상 6층 | 21600 | 12600.1 | 21200
7668795 | 지상 6층 | 1.26001 | 13000 | 지상 6층 | 레벨 : 지상 6층 | 21600 | 12600.1 | 21200
7668810 | 지상 6층 | 1.23 | 12900 | 지상 6층 | 레벨 : 지상 6층 | 21600 | 12300 | 21200
7668811 | 지상 6층 | 1.23 | 12900 | 지상 6층 | 레벨 : 지상 6층 | 21600 | 12300 | 21200
7668812 | 지상 6층 | 1.26001 | 13000 | 지상 6층 | 레벨 : 지상 6층 | 21600 | 12600.1 | 21200
7668813 | 지상 6층 | 1.26001 | 13000 | 지상 6층 | 레벨 : 지상 6층 | 21600 | 12600.1 | 21200
7668821 | 지상 7층 | 1.23 | 12900 | 지상 7층 | 레벨 : 지상 7층 | 25700 | 12300 | 25300
7668843 | 지상 7층 | 1.25 | 13000 | 지상 7층 | 레벨 : 지상 7층 | 25700 | 12500 | 25300
7668852 | 지상 7층 | 1.26001 | 13000 | 지상 7층 | 레벨 : 지상 7층 | 25700 | 12600.1 | 25300
7668853 | 지상 7층 | 1.26001 | 13000 | 지상 7층 | 레벨 : 지상 7층 | 25700 | 12600.1 | 25300
7668868 | 지상 7층 | 1.23 | 12900 | 지상 7층 | 레벨 : 지상 7층 | 25700 | 12300 | 25300
7668869 | 지상 7층 | 1.23 | 12900 | 지상 7층 | 레벨 : 지상 7층 | 25700 | 12300 | 25300
7668870 | 지상 7층 | 1.26001 | 13000 | 지상 7층 | 레벨 : 지상 7층 | 25700 | 12600.1 | 25300
7668871 | 지상 7층 | 1.26001 | 13000 | 지상 7층 | 레벨 : 지상 7층 | 25700 | 12600.1 | 25300
7668879 | 지상 8층 | 1.23 | 12900 | 지상 8층 | 레벨 : 지상 8층 | 29800 | 12300 | 29400
7668901 | 지상 8층 | 1.25 | 13000 | 지상 8층 | 레벨 : 지상 8층 | 29800 | 12500 | 29400
7668910 | 지상 8층 | 1.26001 | 13000 | 지상 8층 | 레벨 : 지상 8층 | 29800 | 12600.1 | 29400
7668911 | 지상 8층 | 1.26001 | 13000 | 지상 8층 | 레벨 : 지상 8층 | 29800 | 12600.1 | 29400
7668926 | 지상 8층 | 1.23 | 12900 | 지상 8층 | 레벨 : 지상 8층 | 29800 | 12300 | 29400
7668927 | 지상 8층 | 1.23 | 12900 | 지상 8층 | 레벨 : 지상 8층 | 29800 | 12300 | 29400
7668928 | 지상 8층 | 1.26001 | 13000 | 지상 8층 | 레벨 : 지상 8층 | 29800 | 12600.1 | 29400
7668929 | 지상 8층 | 1.26001 | 13000 | 지상 8층 | 레벨 : 지상 8층 | 29800 | 12600.1 | 29400
7668937 | 지상 9층 | 1.23 | 12900 | 지상 9층 | 레벨 : 지상 9층 | 33900 | 12300 | 33500
7668959 | 지상 9층 | 1.25 | 13000 | 지상 9층 | 레벨 : 지상 9층 | 33900 | 12500 | 33500
7668968 | 지상 9층 | 1.26001 | 13000 | 지상 9층 | 레벨 : 지상 9층 | 33900 | 12600.1 | 33500
7668969 | 지상 9층 | 1.26001 | 13000 | 지상 9층 | 레벨 : 지상 9층 | 33900 | 12600.1 | 33500
7668984 | 지상 9층 | 1.23 | 12900 | 지상 9층 | 레벨 : 지상 9층 | 33900 | 12300 | 33500
7668985 | 지상 9층 | 1.23 | 12900 | 지상 9층 | 레벨 : 지상 9층 | 33900 | 12300 | 33500
7668986 | 지상 9층 | 1.26001 | 13000 | 지상 9층 | 레벨 : 지상 9층 | 33900 | 12600.1 | 33500
7668987 | 지상 9층 | 1.26001 | 13000 | 지상 9층 | 레벨 : 지상 9층 | 33900 | 12600.1 | 33500
7668995 | 지상 10층 | 1.23 | 12900 | 지상 10층 | 레벨 : 지상 10층 | 38400 | 12300 | 38000
7669017 | 지상 10층 | 1.25 | 13000 | 지상 10층 | 레벨 : 지상 10층 | 38400 | 12500 | 38000
7669026 | 지상 10층 | 1.26001 | 13000 | 지상 10층 | 레벨 : 지상 10층 | 38400 | 12600.1 | 38000
7669027 | 지상 10층 | 1.26001 | 13000 | 지상 10층 | 레벨 : 지상 10층 | 38400 | 12600.1 | 38000
7669042 | 지상 10층 | 1.23 | 12900 | 지상 10층 | 레벨 : 지상 10층 | 38400 | 12300 | 38000
7669043 | 지상 10층 | 1.23 | 12900 | 지상 10층 | 레벨 : 지상 10층 | 38400 | 12300 | 38000
7669044 | 지상 10층 | 1.26001 | 13000 | 지상 10층 | 레벨 : 지상 10층 | 38400 | 12600.1 | 38000
7669045 | 지상 10층 | 1.26001 | 13000 | 지상 10층 | 레벨 : 지상 10층 | 38400 | 12600.1 | 38000

# IfcBeam: BM111-철근콘크리트구조 보:BM110-철근 콘크리트구조 보_400 x 400_2-10B4 (9)
Type - PredefinedType: BEAM; Material: KBIMS-콘크리트
Type - ID 데이터 - 유형 마크: B4; 유형 이름: BM110-철근 콘크리트구조 보_400 x 400_2-10B4
Type - 구조 - 단면 모양: 0
Type - 기타 - 내화구조여부: yes; 주요구조부여부: yes; 카테고리: 구조 프레임; KBIMS-부위코드: E23; 제작정보: bSK-2021_KBIMS2.0-bC; 조달청표준공사코드: AD; 패밀리 이름: BM111-철근콘크리트구조 보
Type - 재료 및 마감재 - 구조 재료: KBIMS-콘크리트
Type - 치수 - 가로치수: 400 mm; 세로치수: 400 mm
Type - Pset_BeamCommon - IsExternal: no; LoadBearing: yes
Pset_BeamCommon - Slope: 0 deg; Reference: BM110-철근 콘크리트구조 보_400 x 400_2-10B4
Pset_QuantityTakeOff - Reference: BM110-철근 콘크리트구조 보_400 x 400_2-10B4; sets with these values: 2
BaseQuantities - CrossSectionArea: 0.075 m2
ID 데이터 - 연관 있음: no
공정 - 생성 공정: 새 구성
구속조건 - 끝 레벨 간격띄우기: 0 mm; 단면형상 회전: 0 deg; 방향: 보통; 시작 레벨 간격띄우기: 0 mm
구조 - 보강 철근 피복 - 다른 면: 보강 철근 피복 1 <25 mm>; 보강 철근 피복 - 하단 면: 보강 철근 피복 1 <25 mm>; 구조적 용도: 기타
기타 - 패밀리: BM111-철근콘크리트구조 보; 유형: BM110-철근 콘크리트구조 보_400 x 400_2-10B4; 유형 ID: 7669413; 패밀리 및 유형: BM111-철근콘크리트구조 보: BM110-철근 콘크리트구조 보_400 x 400_2-10B4
기하학적 위치 - yz 맞춤: 균일; y 간격띄우기 값: 0 mm; y 맞춤: 원점; z 간격띄우기 값: 0 mm; z 맞춤: 상단; 결합 상태: 두 결합 모두 사용
치수 - 단면적: 0.16 m2
Name (BM111-철근콘크리트구조 보:BM110-철근 콘크리트구조 보_400 x 400_2-10B4:...) | In | Span (mm) = 길이 (mm) | Length (mm) | OuterSurfaceArea (m2) | GrossSurfaceArea (m2) | GrossVolume (m3) | NetVolume (m3) = 체적 (m3) | NetSurfaceArea (m2) | 참조 레벨 | 작업 기준면 | 참조 레벨 입면도 (mm) = 상단 기준 레벨 (mm) | 절단 길이 (mm) | 하단 기준 레벨 (mm)
7668387 | 지상 2층 | 5450 | 600 | 0.66 | 0.81 | 0.045 | 0.36 | 5.58 | 지상 2층 | 레벨 : 지상 2층 | 4800 | 5000 | 4400
7668445 | 지상 3층 | 5500 | 700 | 0.77 | 0.92 | 0.0525 | 0.3675 | 5.69 | 지상 3층 | 레벨 : 지상 3층 | 9300 | 5100 | 8900
7668692 | 지상 4층 | 5500 | 700 | 0.77 | 0.92 | 0.0525 | 0.3675 | 5.69 | 지상 4층 | 레벨 : 지상 4층 | 13400 | 5100 | 13000
7668750 | 지상 5층 | 5500 | 700 | 0.77 | 0.92 | 0.0525 | 0.3675 | 5.69 | 지상 5층 | 레벨 : 지상 5층 | 17500 | 5100 | 17100
7668808 | 지상 6층 | 5500 | 700 | 0.77 | 0.92 | 0.0525 | 0.3675 | 5.69 | 지상 6층 | 레벨 : 지상 6층 | 21600 | 5100 | 21200
7668866 | 지상 7층 | 5500 | 700 | 0.77 | 0.92 | 0.0525 | 0.3675 | 5.69 | 지상 7층 | 레벨 : 지상 7층 | 25700 | 5100 | 25300
7668924 | 지상 8층 | 5500 | 700 | 0.77 | 0.92 | 0.0525 | 0.3675 | 5.69 | 지상 8층 | 레벨 : 지상 8층 | 29800 | 5100 | 29400
7668982 | 지상 9층 | 5500 | 700 | 0.77 | 0.92 | 0.0525 | 0.3675 | 5.69 | 지상 9층 | 레벨 : 지상 9층 | 33900 | 5100 | 33500
7669040 | 지상 10층 | 5500 | 700 | 0.77 | 0.92 | 0.0525 | 0.3675 | 5.69 | 지상 10층 | 레벨 : 지상 10층 | 38400 | 5100 | 38000

# IfcBeam: BM111-철근콘크리트구조 보:BM110-철근 콘크리트구조 보_400 x 400_2-10B4 (9)
Type - ID 데이터 - 유형 마크: B4; 유형 이름: BM110-철근 콘크리트구조 보_400 x 400_2-10B4
Type - 구조 - 단면 모양: 0
Type - 기타 - 내화구조여부: yes; 주요구조부여부: yes; 카테고리: 구조 프레임; KBIMS-부위코드: E23; 제작정보: bSK-2021_KBIMS2.0-bC; 조달청표준공사코드: AD; 패밀리 이름: BM111-철근콘크리트구조 보
Type - 재료 및 마감재 - 구조 재료: KBIMS-콘크리트
Type - 치수 - 가로치수: 400 mm; 세로치수: 400 mm
Type - Pset_BeamCommon - IsExternal: no; LoadBearing: yes
Material: KBIMS-콘크리트
BaseQuantities - CrossSectionArea: 0.0500043 m2
Pset_BeamCommon - Slope: 0 deg; Reference: BM110-철근 콘크리트구조 보_400 x 400_2-10B4; Span: 6900 mm
Pset_QuantityTakeOff - Reference: BM110-철근 콘크리트구조 보_400 x 400_2-10B4; sets with these values: 2
ID 데이터 - 연관 있음: no
공정 - 생성 공정: 새 구성
구속조건 - 끝 레벨 간격띄우기: 0 mm; 단면형상 회전: 0 deg; 방향: 보통; 시작 레벨 간격띄우기: 0 mm
구조 - 보강 철근 피복 - 다른 면: 보강 철근 피복 1 <25 mm>; 보강 철근 피복 - 하단 면: 보강 철근 피복 1 <25 mm>; 구조적 용도: 기타
기타 - 패밀리: BM111-철근콘크리트구조 보; 유형: BM110-철근 콘크리트구조 보_400 x 400_2-10B4; 유형 ID: 7669413; 패밀리 및 유형: BM111-철근콘크리트구조 보: BM110-철근 콘크리트구조 보_400 x 400_2-10B4
기하학적 위치 - yz 맞춤: 균일; y 간격띄우기 값: 0 mm; y 맞춤: 원점; z 간격띄우기 값: 0 mm; z 맞춤: 상단; 결합 상태: 두 결합 모두 사용
치수 - 길이: 6900 mm; 단면적: 0.16 m2
Name (BM111-철근콘크리트구조 보:BM110-철근 콘크리트구조 보_400 x 400_2-10B4:...) | In | NetVolume (m3) = 체적 (m3) | 참조 레벨 | 작업 기준면 | 참조 레벨 입면도 (mm) = 상단 기준 레벨 (mm) | 절단 길이 (mm) | 하단 기준 레벨 (mm)
7668385 | 지상 2층 | 0.325028 | 지상 2층 | 레벨 : 지상 2층 | 4800 | 6500 | 4400
7668443 | 지상 3층 | 0.325003 | 지상 3층 | 레벨 : 지상 3층 | 9300 | 6499.5 | 8900
7668690 | 지상 4층 | 0.34503 | 지상 4층 | 레벨 : 지상 4층 | 13400 | 6900 | 13000 | 구조 - 보강 철근 피복 - 상단 면: 보강 철근 피복 1 <25 mm>
7668748 | 지상 5층 | 0.325003 | 지상 5층 | 레벨 : 지상 5층 | 17500 | 6499.5 | 17100
7668806 | 지상 6층 | 0.325003 | 지상 6층 | 레벨 : 지상 6층 | 21600 | 6499.5 | 21200
7668864 | 지상 7층 | 0.325003 | 지상 7층 | 레벨 : 지상 7층 | 25700 | 6499.5 | 25300
7668922 | 지상 8층 | 0.325003 | 지상 8층 | 레벨 : 지상 8층 | 29800 | 6499.5 | 29400
7668980 | 지상 9층 | 0.325003 | 지상 9층 | 레벨 : 지상 9층 | 33900 | 6499.5 | 33500
7669038 | 지상 10층 | 0.34503 | 지상 10층 | 레벨 : 지상 10층 | 38400 | 6900 | 38000 | 구조 - 보강 철근 피복 - 상단 면: 보강 철근 피복 1 <25 mm>

# IfcBeam: BM111-철근콘크리트구조 보:BM110-철근 콘크리트구조 보_400 x 400_2-10B5 (8)
Type - PredefinedType: BEAM; Material: KBIMS-콘크리트
Type - ID 데이터 - 유형 마크: B5; 유형 이름: BM110-철근 콘크리트구조 보_400 x 400_2-10B5
Type - 구조 - 단면 모양: 0
Type - 기타 - 내화구조여부: yes; 주요구조부여부: yes; 카테고리: 구조 프레임; KBIMS-부위코드: E23; 제작정보: bSK-2021_KBIMS2.0-bC; 조달청표준공사코드: AD; 패밀리 이름: BM111-철근콘크리트구조 보
Type - 재료 및 마감재 - 구조 재료: KBIMS-콘크리트
Type - 치수 - 가로치수: 400 mm; 세로치수: 400 mm
Type - Pset_BeamCommon - IsExternal: no; LoadBearing: yes
Pset_BeamCommon - Slope: 0 deg; Reference: BM110-철근 콘크리트구조 보_400 x 400_2-10B5; Span: 5300 mm
Pset_QuantityTakeOff - Reference: BM110-철근 콘크리트구조 보_400 x 400_2-10B5; sets with these values: 2
BaseQuantities - Length: 3199.99 mm
ID 데이터 - 연관 있음: no
공정 - 생성 공정: 새 구성
구속조건 - 끝 레벨 간격띄우기: 0 mm; 단면형상 회전: 0 deg; 방향: 보통; 시작 레벨 간격띄우기: 0 mm
구조 - 보강 철근 피복 - 다른 면: 보강 철근 피복 1 <25 mm>; 보강 철근 피복 - 하단 면: 보강 철근 피복 1 <25 mm>; 구조적 용도: 기타; 절단 길이: 5100 mm
기타 - 패밀리: BM111-철근콘크리트구조 보; 유형: BM110-철근 콘크리트구조 보_400 x 400_2-10B5; 유형 ID: 7669414; 패밀리 및 유형: BM111-철근콘크리트구조 보: BM110-철근 콘크리트구조 보_400 x 400_2-10B5
기하학적 위치 - yz 맞춤: 균일; y 간격띄우기 값: 0 mm; y 맞춤: 원점; z 간격띄우기 값: 0 mm; z 맞춤: 상단; 결합 상태: 두 결합 모두 사용
치수 - 길이: 5300 mm; 단면적: 0.16 m2
Name (BM111-철근콘크리트구조 보:BM110-철근 콘크리트구조 보_400 x 400_2-10B5:...) | In | CrossSectionArea (m2) | OuterSurfaceArea (m2) | GrossSurfaceArea (m2) | GrossVolume (m3) | NetVolume (m3) = 체적 (m3) | NetSurfaceArea (m2) | 참조 레벨 | 작업 기준면 | 참조 레벨 입면도 (mm) = 상단 기준 레벨 (mm) | 보강 철근 피복 - 상단 면 | 하단 기준 레벨 (mm)
7668446 | 지상 3층 | 0.04 | 2.55999 | 2.63999 | 0.128 | 0.329999 | 6.66999 | 지상 3층 | 레벨 : 지상 3층 | 9300 | 보강 철근 피복 1 <25 mm> | 8900
7668693 | 지상 4층 | 0.04 | 2.55999 | 2.63999 | 0.128 | 0.329999 | 6.66999 | 지상 4층 | 레벨 : 지상 4층 | 13400 | 보강 철근 피복 1 <25 mm> | 13000
7668751 | 지상 5층 | 0.04 | 2.55999 | 2.63999 | 0.128 | 0.329999 | 6.66999 | 지상 5층 | 레벨 : 지상 5층 | 17500 | 보강 철근 피복 1 <25 mm> | 17100
7668809 | 지상 6층 | 0.04 | 2.55999 | 2.63999 | 0.128 | 0.329999 | 6.66999 | 지상 6층 | 레벨 : 지상 6층 | 21600 | 보강 철근 피복 1 <25 mm> | 21200
7668867 | 지상 7층 | 0.04 | 2.55999 | 2.63999 | 0.128 | 0.329999 | 6.66999 | 지상 7층 | 레벨 : 지상 7층 | 25700 | 보강 철근 피복 1 <25 mm> | 25300
7668925 | 지상 8층 | 0.04 | 2.55999 | 2.63999 | 0.128 | 0.329999 | 6.66999 | 지상 8층 | 레벨 : 지상 8층 | 29800 | 보강 철근 피복 1 <25 mm> | 29400
7668983 | 지상 9층 | 0.04 | 2.55999 | 2.63999 | 0.128 | 0.329999 | 6.66999 | 지상 9층 | 레벨 : 지상 9층 | 33900 | 보강 철근 피복 1 <25 mm> | 33500
7669041 | 지상 10층 | 0.048 | 2.81599 | 2.91199 | 0.153599 | 0.323599 | 5.322 | 지상 10층 | 레벨 : 지상 10층 | 38400 |  | 38000

# IfcBeam: BM111-철근콘크리트구조 보:BM110-철근 콘크리트구조 보_400 x 400_2-10B5 (9)
Type - ID 데이터 - 유형 마크: B5; 유형 이름: BM110-철근 콘크리트구조 보_400 x 400_2-10B5
Type - 구조 - 단면 모양: 0
Type - 기타 - 내화구조여부: yes; 주요구조부여부: yes; 카테고리: 구조 프레임; KBIMS-부위코드: E23; 제작정보: bSK-2021_KBIMS2.0-bC; 조달청표준공사코드: AD; 패밀리 이름: BM111-철근콘크리트구조 보
Type - 재료 및 마감재 - 구조 재료: KBIMS-콘크리트
Type - 치수 - 가로치수: 400 mm; 세로치수: 400 mm
Type - Pset_BeamCommon - IsExternal: no; LoadBearing: yes
Material: KBIMS-콘크리트
Pset_BeamCommon - Slope: 0 deg; Reference: BM110-철근 콘크리트구조 보_400 x 400_2-10B5
Pset_QuantityTakeOff - Reference: BM110-철근 콘크리트구조 보_400 x 400_2-10B5; sets with these values: 2
ID 데이터 - 연관 있음: no
공정 - 생성 공정: 새 구성
구속조건 - 끝 레벨 간격띄우기: 0 mm; 단면형상 회전: 0 deg; 방향: 보통; 시작 레벨 간격띄우기: 0 mm
구조 - 보강 철근 피복 - 다른 면: 보강 철근 피복 1 <25 mm>; 보강 철근 피복 - 상단 면: 보강 철근 피복 1 <25 mm>; 보강 철근 피복 - 하단 면: 보강 철근 피복 1 <25 mm>; 구조적 용도: 기타
기타 - 패밀리: BM111-철근콘크리트구조 보; 유형: BM110-철근 콘크리트구조 보_400 x 400_2-10B5; 유형 ID: 7669414; 패밀리 및 유형: BM111-철근콘크리트구조 보: BM110-철근 콘크리트구조 보_400 x 400_2-10B5
기하학적 위치 - yz 맞춤: 균일; y 간격띄우기 값: 0 mm; y 맞춤: 원점; z 간격띄우기 값: 0 mm; z 맞춤: 상단; 결합 상태: 두 결합 모두 사용
치수 - 단면적: 0.16 m2
Name (BM111-철근콘크리트구조 보:BM110-철근 콘크리트구조 보_400 x 400_2-10B5:...) | In | CrossSectionArea (m2) | NetVolume (m3) = 체적 (m3) | Span (mm) = 길이 (mm) | 참조 레벨 | 작업 기준면 | 참조 레벨 입면도 (mm) = 상단 기준 레벨 (mm) | 절단 길이 (mm) | 하단 기준 레벨 (mm)
7668393 | 지상 2층 | 2.83002 | 0.348001 | 2950 | 지상 2층 | 레벨 : 지상 2층 | 4800 | 2800.02 | 4400
7668451 | 지상 3층 | 2.78499 | 0.343001 | 3050 | 지상 3층 | 레벨 : 지상 3층 | 9300 | 2700.01 | 8900
7668698 | 지상 4층 | 3.01 | 0.368003 | 3050 | 지상 4층 | 레벨 : 지상 4층 | 13400 | 3000.03 | 13000
7668756 | 지상 5층 | 3.01 | 0.368003 | 3050 | 지상 5층 | 레벨 : 지상 5층 | 17500 | 3000.03 | 17100
7668814 | 지상 6층 | 3.01 | 0.368003 | 3050 | 지상 6층 | 레벨 : 지상 6층 | 21600 | 3000.03 | 21200
7668872 | 지상 7층 | 2.78499 | 0.343001 | 3050 | 지상 7층 | 레벨 : 지상 7층 | 25700 | 2700.01 | 25300
7668930 | 지상 8층 | 2.78499 | 0.343001 | 3050 | 지상 8층 | 레벨 : 지상 8층 | 29800 | 2700.01 | 29400
7668988 | 지상 9층 | 2.78499 | 0.343001 | 3050 | 지상 9층 | 레벨 : 지상 9층 | 33900 | 2700.01 | 33500
7669046 | 지상 10층 | 2.255 | 0.337801 | 3050 | 지상 10층 | 레벨 : 지상 10층 | 38400 | 2700.01 | 38000

# IfcBeam: BM111-철근콘크리트구조 보:BM110-철근 콘크리트구조 보_400 x 400_2-10G1 (18)
Type - ID 데이터 - 유형 마크: G1; 유형 이름: BM110-철근 콘크리트구조 보_400 x 400_2-10G1
Type - 구조 - 단면 모양: 0
Type - 기타 - 내화구조여부: yes; 주요구조부여부: yes; 카테고리: 구조 프레임; KBIMS-부위코드: E23; 제작정보: bSK-2021_KBIMS2.0-bC; 조달청표준공사코드: AD; 패밀리 이름: BM111-철근콘크리트구조 보
Type - 재료 및 마감재 - 구조 재료: KBIMS-콘크리트
Type - 치수 - 가로치수: 400 mm; 세로치수: 400 mm
Type - Pset_BeamCommon - IsExternal: no; LoadBearing: yes
Material: KBIMS-콘크리트
Pset_BeamCommon - Slope: 0 deg; Reference: BM110-철근 콘크리트구조 보_400 x 400_2-10G1
Pset_QuantityTakeOff - Reference: BM110-철근 콘크리트구조 보_400 x 400_2-10G1; sets with these values: 2
ID 데이터 - 연관 있음: no
공정 - 생성 공정: 새 구성
구속조건 - 끝 레벨 간격띄우기: 0 mm; 단면형상 회전: 0 deg; 방향: 보통; 시작 레벨 간격띄우기: 0 mm
구조 - 보강 철근 피복 - 다른 면: 보강 철근 피복 1 <25 mm>; 보강 철근 피복 - 하단 면: 보강 철근 피복 1 <25 mm>; 구조적 용도: 기타; 시작 부착 유형: 끝 입면; 끝 부착 유형: 끝 입면
기타 - 패밀리: BM111-철근콘크리트구조 보; 유형: BM110-철근 콘크리트구조 보_400 x 400_2-10G1; 유형 ID: 7669420; 패밀리 및 유형: BM111-철근콘크리트구조 보: BM110-철근 콘크리트구조 보_400 x 400_2-10G1
기하학적 위치 - yz 맞춤: 균일; y 간격띄우기 값: 0 mm; y 맞춤: 원점; z 간격띄우기 값: 0 mm; z 맞춤: 상단; 결합 상태: 두 결합 모두 사용
치수 - 단면적: 0.16 m2
Name (BM111-철근콘크리트구조 보:BM110-철근 콘크리트구조 보_400 x 400_2-10G1:...) | In | CrossSectionArea (m2) | NetVolume (m3) = 체적 (m3) | Span (mm) = 길이 (mm) | 참조 레벨 | 작업 기준면 | 참조 레벨 입면도 (mm) = 상단 기준 레벨 (mm) | 절단 길이 (mm) | 하단 기준 레벨 (mm)
7668349 | 지상 2층 | 0.1 | 0.909999 | 9700 | 지상 2층 | 레벨 : 지상 2층 | 4800 | 9099.99 | 4400 | 구조 - 보강 철근 피복 - 상단 면: 보강 철근 피복 1 <25 mm>
7668371 | 지상 2층 | 0.0499999 | 0.455 | 10100 | 지상 2층 | 레벨 : 지상 2층 | 4800 | 9100.01 | 4400
7668407 | 지상 3층 | 0.1 | 0.910001 | 9650 | 지상 3층 | 레벨 : 지상 3층 | 9300 | 9100.01 | 8900 | 구조 - 보강 철근 피복 - 상단 면: 보강 철근 피복 1 <25 mm>
7668429 | 지상 3층 | 0.0499999 | 0.455 | 10100 | 지상 3층 | 레벨 : 지상 3층 | 9300 | 9100.01 | 8900
7668654 | 지상 4층 | 0.1 | 0.910001 | 9650 | 지상 4층 | 레벨 : 지상 4층 | 13400 | 9100.01 | 13000 | 구조 - 보강 철근 피복 - 상단 면: 보강 철근 피복 1 <25 mm>
7668676 | 지상 4층 | 0.0499999 | 0.455 | 10100 | 지상 4층 | 레벨 : 지상 4층 | 13400 | 9100.01 | 13000
7668712 | 지상 5층 | 0.1 | 0.910001 | 9650 | 지상 5층 | 레벨 : 지상 5층 | 17500 | 9100.01 | 17100 | 구조 - 보강 철근 피복 - 상단 면: 보강 철근 피복 1 <25 mm>
7668734 | 지상 5층 | 0.0499999 | 0.455 | 10100 | 지상 5층 | 레벨 : 지상 5층 | 17500 | 9100.01 | 17100
7668770 | 지상 6층 | 0.1 | 0.930001 | 10050 | 지상 6층 | 레벨 : 지상 6층 | 21600 | 9300.01 | 21200 | 구조 - 보강 철근 피복 - 상단 면: 보강 철근 피복 1 <25 mm>
7668792 | 지상 6층 | 0.0499999 | 0.465 | 10100 | 지상 6층 | 레벨 : 지상 6층 | 21600 | 9300.01 | 21200
7668828 | 지상 7층 | 0.1 | 0.930001 | 10050 | 지상 7층 | 레벨 : 지상 7층 | 25700 | 9300.01 | 25300 | 구조 - 보강 철근 피복 - 상단 면: 보강 철근 피복 1 <25 mm>
7668850 | 지상 7층 | 0.0499999 | 0.465 | 10100 | 지상 7층 | 레벨 : 지상 7층 | 25700 | 9300.01 | 25300
7668886 | 지상 8층 | 0.1 | 0.930001 | 10050 | 지상 8층 | 레벨 : 지상 8층 | 29800 | 9300.01 | 29400 | 구조 - 보강 철근 피복 - 상단 면: 보강 철근 피복 1 <25 mm>
7668908 | 지상 8층 | 0.0499999 | 0.465 | 10100 | 지상 8층 | 레벨 : 지상 8층 | 29800 | 9300.01 | 29400
7668944 | 지상 9층 | 0.1 | 0.930001 | 10050 | 지상 9층 | 레벨 : 지상 9층 | 33900 | 9300.01 | 33500 | 구조 - 보강 철근 피복 - 상단 면: 보강 철근 피복 1 <25 mm>
7668966 | 지상 9층 | 0.0499999 | 0.465 | 10100 | 지상 9층 | 레벨 : 지상 9층 | 33900 | 9300.01 | 33500
7669002 | 지상 10층 | 0.1 | 0.930001 | 10050 | 지상 10층 | 레벨 : 지상 10층 | 38400 | 9300.01 | 38000 | 구조 - 보강 철근 피복 - 상단 면: 보강 철근 피복 1 <25 mm>
7669024 | 지상 10층 | 4.339 | 0.466 | 10100 | 지상 10층 | 레벨 : 지상 10층 | 38400 | 9300.01 | 38000

# IfcBeam: BM111-철근콘크리트구조 보:BM110-철근 콘크리트구조 보_400 x 400_2-10G10 (36)
Type - ID 데이터 - 유형 마크: G10; 유형 이름: BM110-철근 콘크리트구조 보_400 x 400_2-10G10
Type - 구조 - 단면 모양: 0
Type - 기타 - 내화구조여부: yes; 주요구조부여부: yes; 카테고리: 구조 프레임; KBIMS-부위코드: E23; 제작정보: bSK-2021_KBIMS2.0-bC; 조달청표준공사코드: AD; 패밀리 이름: BM111-철근콘크리트구조 보
Type - 재료 및 마감재 - 구조 재료: KBIMS-콘크리트
Type - 치수 - 가로치수: 400 mm; 세로치수: 400 mm
Type - Pset_BeamCommon - IsExternal: no; LoadBearing: yes
Material: KBIMS-콘크리트
Pset_BeamCommon - Slope: 0 deg; Reference: BM110-철근 콘크리트구조 보_400 x 400_2-10G10
Pset_QuantityTakeOff - Reference: BM110-철근 콘크리트구조 보_400 x 400_2-10G10; sets with these values: 2
ID 데이터 - 연관 있음: no
공정 - 생성 공정: 새 구성
구속조건 - 끝 레벨 간격띄우기: 0 mm; 단면형상 회전: 0 deg; 방향: 보통; 시작 레벨 간격띄우기: 0 mm
구조 - 보강 철근 피복 - 다른 면: 보강 철근 피복 1 <25 mm>; 보강 철근 피복 - 하단 면: 보강 철근 피복 1 <25 mm>; 시작 부착 유형: 끝 입면; 구조적 용도: 거더; 끝 부착 유형: 끝 입면
기타 - 패밀리: BM111-철근콘크리트구조 보; 유형: BM110-철근 콘크리트구조 보_400 x 400_2-10G10; 유형 ID: 7669423; 패밀리 및 유형: BM111-철근콘크리트구조 보: BM110-철근 콘크리트구조 보_400 x 400_2-10G10
기하학적 위치 - yz 맞춤: 균일; y 간격띄우기 값: 0 mm; y 맞춤: 원점; z 간격띄우기 값: 0 mm; z 맞춤: 상단; 결합 상태: 두 결합 모두 사용
치수 - 단면적: 0.16 m2
Name (BM111-철근콘크리트구조 보:BM110-철근 콘크리트구조 보_400 x 400_2-10G10:...) | In | CrossSectionArea (m2) | NetVolume (m3) = 체적 (m3) | Span (mm) = 길이 (mm) | 참조 레벨 | 작업 기준면 | 참조 레벨 입면도 (mm) = 상단 기준 레벨 (mm) | 절단 길이 (mm) | 하단 기준 레벨 (mm)
7668365 | 지상 2층 | 0.1 | 0.66 | 7600 | 지상 2층 | 레벨 : 지상 2층 | 4800 | 6600 | 4400
7668366 | 지상 2층 | 0.1 | 0.66 | 7250 | 지상 2층 | 레벨 : 지상 2층 | 4800 | 6600 | 4400 | 구조 - 보강 철근 피복 - 상단 면: 보강 철근 피복 1 <25 mm>
7668372 | 지상 2층 | 0.1 | 0.72 | 7800 | 지상 2층 | 레벨 : 지상 2층 | 4800 | 7200 | 4400
7668375 | 지상 2층 | 0.1 | 0.72 | 7400 | 지상 2층 | 레벨 : 지상 2층 | 4800 | 7200 | 4400 | 구조 - 보강 철근 피복 - 상단 면: 보강 철근 피복 1 <25 mm>
7668423 | 지상 3층 | 0.0812457 | 0.536221 | 7800 | 지상 3층 | 레벨 : 지상 3층 | 9300 | 6600 | 8900
7668424 | 지상 3층 | 0.1 | 0.66 | 7400 | 지상 3층 | 레벨 : 지상 3층 | 9300 | 6600 | 8900 | 구조 - 보강 철근 피복 - 상단 면: 보강 철근 피복 1 <25 mm>
7668430 | 지상 3층 | 0.0687456 | 0.494969 | 7800 | 지상 3층 | 레벨 : 지상 3층 | 9300 | 7200 | 8900
7668433 | 지상 3층 | 0.1 | 0.72 | 7600 | 지상 3층 | 레벨 : 지상 3층 | 9300 | 7200 | 8900 | 구조 - 보강 철근 피복 - 상단 면: 보강 철근 피복 1 <25 mm>
7668670 | 지상 4층 | 0.1 | 0.66 | 7800 | 지상 4층 | 레벨 : 지상 4층 | 13400 | 6600 | 13000
7668671 | 지상 4층 | 0.1 | 0.66 | 7400 | 지상 4층 | 레벨 : 지상 4층 | 13400 | 6600 | 13000 | 구조 - 보강 철근 피복 - 상단 면: 보강 철근 피복 1 <25 mm>
7668677 | 지상 4층 | 0.1 | 0.72 | 7800 | 지상 4층 | 레벨 : 지상 4층 | 13400 | 7200 | 13000
7668680 | 지상 4층 | 0.1 | 0.72 | 7600 | 지상 4층 | 레벨 : 지상 4층 | 13400 | 7200 | 13000 | 구조 - 보강 철근 피복 - 상단 면: 보강 철근 피복 1 <25 mm>
7668728 | 지상 5층 | 0.1 | 0.66 | 7800 | 지상 5층 | 레벨 : 지상 5층 | 17500 | 6600 | 17100
7668729 | 지상 5층 | 0.1 | 0.66 | 7400 | 지상 5층 | 레벨 : 지상 5층 | 17500 | 6600 | 17100 | 구조 - 보강 철근 피복 - 상단 면: 보강 철근 피복 1 <25 mm>
7668735 | 지상 5층 | 0.1 | 0.72 | 7800 | 지상 5층 | 레벨 : 지상 5층 | 17500 | 7200 | 17100
7668738 | 지상 5층 | 0.1 | 0.72 | 7600 | 지상 5층 | 레벨 : 지상 5층 | 17500 | 7200 | 17100 | 구조 - 보강 철근 피복 - 상단 면: 보강 철근 피복 1 <25 mm>
7668786 | 지상 6층 | 0.1 | 0.66 | 7800 | 지상 6층 | 레벨 : 지상 6층 | 21600 | 6600 | 21200
7668787 | 지상 6층 | 0.1 | 0.66 | 7400 | 지상 6층 | 레벨 : 지상 6층 | 21600 | 6600 | 21200 | 구조 - 보강 철근 피복 - 상단 면: 보강 철근 피복 1 <25 mm>
7668793 | 지상 6층 | 0.1 | 0.72 | 7800 | 지상 6층 | 레벨 : 지상 6층 | 21600 | 7200 | 21200
7668796 | 지상 6층 | 0.1 | 0.72 | 7600 | 지상 6층 | 레벨 : 지상 6층 | 21600 | 7200 | 21200 | 구조 - 보강 철근 피복 - 상단 면: 보강 철근 피복 1 <25 mm>
7668844 | 지상 7층 | 0.1 | 0.66 | 7800 | 지상 7층 | 레벨 : 지상 7층 | 25700 | 6600 | 25300
7668845 | 지상 7층 | 0.1 | 0.66 | 7400 | 지상 7층 | 레벨 : 지상 7층 | 25700 | 6600 | 25300 | 구조 - 보강 철근 피복 - 상단 면: 보강 철근 피복 1 <25 mm>
7668851 | 지상 7층 | 0.1 | 0.72 | 7800 | 지상 7층 | 레벨 : 지상 7층 | 25700 | 7200 | 25300
7668854 | 지상 7층 | 0.1 | 0.72 | 7600 | 지상 7층 | 레벨 : 지상 7층 | 25700 | 7200 | 25300 | 구조 - 보강 철근 피복 - 상단 면: 보강 철근 피복 1 <25 mm>
7668902 | 지상 8층 | 0.1 | 0.66 | 7800 | 지상 8층 | 레벨 : 지상 8층 | 29800 | 6600 | 29400
7668903 | 지상 8층 | 0.1 | 0.66 | 7400 | 지상 8층 | 레벨 : 지상 8층 | 29800 | 6600 | 29400 | 구조 - 보강 철근 피복 - 상단 면: 보강 철근 피복 1 <25 mm>
7668909 | 지상 8층 | 0.1 | 0.72 | 7800 | 지상 8층 | 레벨 : 지상 8층 | 29800 | 7200 | 29400
7668912 | 지상 8층 | 0.1 | 0.72 | 7600 | 지상 8층 | 레벨 : 지상 8층 | 29800 | 7200 | 29400 | 구조 - 보강 철근 피복 - 상단 면: 보강 철근 피복 1 <25 mm>
7668960 | 지상 9층 | 0.1 | 0.68 | 7800 | 지상 9층 | 레벨 : 지상 9층 | 33900 | 6800 | 33500
7668961 | 지상 9층 | 0.1 | 0.680003 | 7400 | 지상 9층 | 레벨 : 지상 9층 | 33900 | 6800.03 | 33500 | 구조 - 보강 철근 피복 - 상단 면: 보강 철근 피복 1 <25 mm>
7668967 | 지상 9층 | 0.1 | 0.73 | 8200 | 지상 9층 | 레벨 : 지상 9층 | 33900 | 7300 | 33500
7668970 | 지상 9층 | 0.1 | 0.73 | 8000 | 지상 9층 | 레벨 : 지상 9층 | 33900 | 7300 | 33500 | 구조 - 보강 철근 피복 - 상단 면: 보강 철근 피복 1 <25 mm>
7669018 | 지상 10층 | 0.1 | 0.68 | 7800 | 지상 10층 | 레벨 : 지상 10층 | 38400 | 6800 | 38000
7669019 | 지상 10층 | 0.1 | 0.680003 | 7400 | 지상 10층 | 레벨 : 지상 10층 | 38400 | 6800.03 | 38000 | 구조 - 보강 철근 피복 - 상단 면: 보강 철근 피복 1 <25 mm>
7669025 | 지상 10층 | 0.1 | 0.73 | 8200 | 지상 10층 | 레벨 : 지상 10층 | 38400 | 7300 | 38000
7669028 | 지상 10층 | 5.52751 | 0.860542 | 8000 | 지상 10층 | 레벨 : 지상 10층 | 38400 | 7300 | 38000 | 구조 - 보강 철근 피복 - 상단 면: 보강 철근 피복 1 <25 mm>

# IfcBeam: BM111-철근콘크리트구조 보:BM110-철근 콘크리트구조 보_400 x 400_2-10G2 (9)
Type - PredefinedType: BEAM; Material: KBIMS-콘크리트
Type - ID 데이터 - 유형 마크: G2; 유형 이름: BM110-철근 콘크리트구조 보_400 x 400_2-10G2
Type - 구조 - 단면 모양: 0
Type - 기타 - 내화구조여부: yes; 주요구조부여부: yes; 카테고리: 구조 프레임; KBIMS-부위코드: E23; 제작정보: bSK-2021_KBIMS2.0-bC; 조달청표준공사코드: AD; 패밀리 이름: BM111-철근콘크리트구조 보
Type - 재료 및 마감재 - 구조 재료: KBIMS-콘크리트
Type - 치수 - 가로치수: 400 mm; 세로치수: 400 mm
Type - Pset_BeamCommon - IsExternal: no; LoadBearing: yes
Pset_BeamCommon - Slope: 0 deg; Reference: BM110-철근 콘크리트구조 보_400 x 400_2-10G2; Span: 7000 mm
Pset_QuantityTakeOff - Reference: BM110-철근 콘크리트구조 보_400 x 400_2-10G2; sets with these values: 2
ID 데이터 - 연관 있음: no
공정 - 생성 공정: 새 구성
구속조건 - 끝 레벨 간격띄우기: 0 mm; 단면형상 회전: 0 deg; 방향: 보통; 시작 레벨 간격띄우기: 0 mm
구조 - 보강 철근 피복 - 다른 면: 보강 철근 피복 1 <25 mm>; 보강 철근 피복 - 하단 면: 보강 철근 피복 1 <25 mm>; 구조적 용도: 거더; 끝 부착 유형: 끝 입면; 절단 길이: 7000 mm
기타 - 패밀리: BM111-철근콘크리트구조 보; 유형: BM110-철근 콘크리트구조 보_400 x 400_2-10G2; 유형 ID: 7669407; 패밀리 및 유형: BM111-철근콘크리트구조 보: BM110-철근 콘크리트구조 보_400 x 400_2-10G2
기하학적 위치 - yz 맞춤: 균일; y 간격띄우기 값: 0 mm; y 맞춤: 원점; z 간격띄우기 값: 0 mm; z 맞춤: 상단; 결합 상태: 두 결합 모두 사용
치수 - 길이: 7000 mm; 단면적: 0.16 m2
Name (BM111-철근콘크리트구조 보:BM110-철근 콘크리트구조 보_400 x 400_2-10G2:...) | In | CrossSectionArea (m2) | NetVolume (m3) = 체적 (m3) | 참조 레벨 | 작업 기준면 | 참조 레벨 입면도 (mm) = 상단 기준 레벨 (mm) | 하단 기준 레벨 (mm)
7668378 | 지상 2층 | 0.0495449 | 0.35 | 지상 2층 | 레벨 : 지상 2층 | 4800 | 4400 | BaseQuantities - Length: 7000 mm; OuterSurfaceArea: 6.27451 m2; GrossSurfaceArea: 6.3736 m2; GrossVolume: 0.346814 m3; NetSurfaceArea: 9.9 m2
7668436 | 지상 3층 | 0.0500043 | 0.35003 | 지상 3층 | 레벨 : 지상 3층 | 9300 | 8900
7668683 | 지상 4층 | 0.0500043 | 0.35003 | 지상 4층 | 레벨 : 지상 4층 | 13400 | 13000
7668741 | 지상 5층 | 0.0500043 | 0.35003 | 지상 5층 | 레벨 : 지상 5층 | 17500 | 17100
7668799 | 지상 6층 | 0.0500043 | 0.35003 | 지상 6층 | 레벨 : 지상 6층 | 21600 | 21200
7668857 | 지상 7층 | 0.0500043 | 0.35003 | 지상 7층 | 레벨 : 지상 7층 | 25700 | 25300
7668915 | 지상 8층 | 0.0500043 | 0.35003 | 지상 8층 | 레벨 : 지상 8층 | 29800 | 29400
7668973 | 지상 9층 | 0.0500043 | 0.35003 | 지상 9층 | 레벨 : 지상 9층 | 33900 | 33500
7669031 | 지상 10층 | 3.89763 | 0.483542 | 지상 10층 | 레벨 : 지상 10층 | 38400 | 38000 | 구조 - 보강 철근 피복 - 상단 면: 보강 철근 피복 1 <25 mm>

# IfcBeam: BM111-철근콘크리트구조 보:BM110-철근 콘크리트구조 보_400 x 400_2-10G3 (18)
Type - ID 데이터 - 유형 마크: G3; 유형 이름: BM110-철근 콘크리트구조 보_400 x 400_2-10G3
Type - 구조 - 단면 모양: 0
Type - 기타 - 내화구조여부: yes; 주요구조부여부: yes; 카테고리: 구조 프레임; KBIMS-부위코드: E23; 제작정보: bSK-2021_KBIMS2.0-bC; 조달청표준공사코드: AD; 패밀리 이름: BM111-철근콘크리트구조 보
Type - 재료 및 마감재 - 구조 재료: KBIMS-콘크리트
Type - 치수 - 가로치수: 400 mm; 세로치수: 400 mm
Type - Pset_BeamCommon - IsExternal: no; LoadBearing: yes
Material: KBIMS-콘크리트
BaseQuantities - CrossSectionArea: 0.1 m2
Pset_BeamCommon - Slope: 0 deg; Reference: BM110-철근 콘크리트구조 보_400 x 400_2-10G3
Pset_QuantityTakeOff - Reference: BM110-철근 콘크리트구조 보_400 x 400_2-10G3; sets with these values: 2
ID 데이터 - 연관 있음: no
공정 - 생성 공정: 새 구성
구속조건 - 끝 레벨 간격띄우기: 0 mm; 단면형상 회전: 0 deg; 방향: 보통; 시작 레벨 간격띄우기: 0 mm
구조 - 보강 철근 피복 - 다른 면: 보강 철근 피복 1 <25 mm>; 보강 철근 피복 - 하단 면: 보강 철근 피복 1 <25 mm>; 구조적 용도: 기타; 시작 부착 유형: 끝 입면
기타 - 패밀리: BM111-철근콘크리트구조 보; 유형: BM110-철근 콘크리트구조 보_400 x 400_2-10G3; 유형 ID: 7669408; 패밀리 및 유형: BM111-철근콘크리트구조 보: BM110-철근 콘크리트구조 보_400 x 400_2-10G3
기하학적 위치 - yz 맞춤: 균일; y 간격띄우기 값: 0 mm; y 맞춤: 원점; z 간격띄우기 값: 0 mm; z 맞춤: 상단; 결합 상태: 두 결합 모두 사용
치수 - 단면적: 0.16 m2
Name (BM111-철근콘크리트구조 보:BM110-철근 콘크리트구조 보_400 x 400_2-10G3:...) | In | NetVolume (m3) = 체적 (m3) | Span (mm) = 길이 (mm) | 참조 레벨 | 작업 기준면 | 참조 레벨 입면도 (mm) = 상단 기준 레벨 (mm) | 절단 길이 (mm) | 하단 기준 레벨 (mm)
7668348 | 지상 2층 | 0.249817 | 2948 | 지상 2층 | 레벨 : 지상 2층 | 4800 | 2498.17 | 4400
7668377 | 지상 2층 | 0.229999 | 2850 | 지상 2층 | 레벨 : 지상 2층 | 4800 | 2299.99 | 4400
7668406 | 지상 3층 | 0.250001 | 2850 | 지상 3층 | 레벨 : 지상 3층 | 9300 | 2500.01 | 8900
7668435 | 지상 3층 | 0.229999 | 2750 | 지상 3층 | 레벨 : 지상 3층 | 9300 | 2299.99 | 8900
7668653 | 지상 4층 | 0.250001 | 2850 | 지상 4층 | 레벨 : 지상 4층 | 13400 | 2500.01 | 13000
7668682 | 지상 4층 | 0.229999 | 2750 | 지상 4층 | 레벨 : 지상 4층 | 13400 | 2299.99 | 13000
7668711 | 지상 5층 | 0.250001 | 2850 | 지상 5층 | 레벨 : 지상 5층 | 17500 | 2500.01 | 17100
7668740 | 지상 5층 | 0.229999 | 2750 | 지상 5층 | 레벨 : 지상 5층 | 17500 | 2299.99 | 17100
7668769 | 지상 6층 | 0.250001 | 2850 | 지상 6층 | 레벨 : 지상 6층 | 21600 | 2500.01 | 21200
7668798 | 지상 6층 | 0.229999 | 2750 | 지상 6층 | 레벨 : 지상 6층 | 21600 | 2299.99 | 21200
7668827 | 지상 7층 | 0.250001 | 2850 | 지상 7층 | 레벨 : 지상 7층 | 25700 | 2500.01 | 25300
7668856 | 지상 7층 | 0.229999 | 2750 | 지상 7층 | 레벨 : 지상 7층 | 25700 | 2299.99 | 25300
7668885 | 지상 8층 | 0.250001 | 2850 | 지상 8층 | 레벨 : 지상 8층 | 29800 | 2500.01 | 29400
7668914 | 지상 8층 | 0.229999 | 2750 | 지상 8층 | 레벨 : 지상 8층 | 29800 | 2299.99 | 29400
7668943 | 지상 9층 | 0.250001 | 2850 | 지상 9층 | 레벨 : 지상 9층 | 33900 | 2500.01 | 33500
7668972 | 지상 9층 | 0.229999 | 2750 | 지상 9층 | 레벨 : 지상 9층 | 33900 | 2299.99 | 33500
7669001 | 지상 10층 | 0.250001 | 2850 | 지상 10층 | 레벨 : 지상 10층 | 38400 | 2500.01 | 38000
7669030 | 지상 10층 | 0.229999 | 2750 | 지상 10층 | 레벨 : 지상 10층 | 38400 | 2299.99 | 38000

# IfcBeam: BM111-철근콘크리트구조 보:BM110-철근 콘크리트구조 보_400 x 400_2-10G4 (18)
Type - PredefinedType: BEAM; Material: KBIMS-콘크리트
Type - ID 데이터 - 유형 마크: G4; 유형 이름: BM110-철근 콘크리트구조 보_400 x 400_2-10G4
Type - 구조 - 단면 모양: 0
Type - 기타 - 내화구조여부: yes; 주요구조부여부: yes; 카테고리: 구조 프레임; KBIMS-부위코드: E23; 제작정보: bSK-2021_KBIMS2.0-bC; 조달청표준공사코드: AD; 패밀리 이름: BM111-철근콘크리트구조 보
Type - 재료 및 마감재 - 구조 재료: KBIMS-콘크리트
Type - 치수 - 가로치수: 400 mm; 세로치수: 400 mm
Type - Pset_BeamCommon - IsExternal: no; LoadBearing: yes
Pset_BeamCommon - Slope: 0 deg; Reference: BM110-철근 콘크리트구조 보_400 x 400_2-10G4
Pset_QuantityTakeOff - Reference: BM110-철근 콘크리트구조 보_400 x 400_2-10G4; sets with these values: 2
ID 데이터 - 연관 있음: no
공정 - 생성 공정: 새 구성
구속조건 - 끝 레벨 간격띄우기: 0 mm; 단면형상 회전: 0 deg; 방향: 보통; 시작 레벨 간격띄우기: 0 mm
구조 - 보강 철근 피복 - 다른 면: 보강 철근 피복 1 <25 mm>; 보강 철근 피복 - 하단 면: 보강 철근 피복 1 <25 mm>; 시작 부착 유형: 끝 입면; 구조적 용도: 거더; 끝 부착 유형: 끝 입면
기타 - 패밀리: BM111-철근콘크리트구조 보; 유형: BM110-철근 콘크리트구조 보_400 x 400_2-10G4; 유형 ID: 7669409; 패밀리 및 유형: BM111-철근콘크리트구조 보: BM110-철근 콘크리트구조 보_400 x 400_2-10G4
기하학적 위치 - yz 맞춤: 균일; y 간격띄우기 값: 0 mm; y 맞춤: 원점; z 간격띄우기 값: 0 mm; z 맞춤: 상단; 결합 상태: 두 결합 모두 사용
치수 - 단면적: 0.16 m2
Name (BM111-철근콘크리트구조 보:BM110-철근 콘크리트구조 보_400 x 400_2-10G4:...) | In | Span (mm) = 길이 (mm) | CrossSectionArea (m2) | NetVolume (m3) = 체적 (m3) | 참조 레벨 | 작업 기준면 | 참조 레벨 입면도 (mm) = 상단 기준 레벨 (mm) | 절단 길이 (mm) | 하단 기준 레벨 (mm)
7668361 | 지상 2층 | 7350 | 0.1 | 0.441867 | 지상 2층 | 레벨 : 지상 2층 | 4800 | 6537.5 | 4400 | BaseQuantities - Length: 2500 mm; OuterSurfaceArea: 3.25 m2; GrossSurfaceArea: 3.45 m2; GrossVolume: 0.25 m3; NetSurfaceArea: 7.00368 m2
7668362 | 지상 2층 | 7250 | 4.36312 | 0.639999 | 지상 2층 | 레벨 : 지상 2층 | 4800 | 6537.5 | 4400
7668419 | 지상 3층 | 7250 | 3.52497 | 0.449991 | 지상 3층 | 레벨 : 지상 3층 | 9300 | 6500 | 8900
7668420 | 지상 3층 | 6950 | 3.51481 | 0.447451 | 지상 3층 | 레벨 : 지상 3층 | 9300 | 6500 | 8900
7668666 | 지상 4층 | 7250 | 3.52597 | 0.450241 | 지상 4층 | 레벨 : 지상 4층 | 13400 | 6500 | 13000
7668667 | 지상 4층 | 6950 | 0.1 | 0.65 | 지상 4층 | 레벨 : 지상 4층 | 13400 | 6500 | 13000
7668724 | 지상 5층 | 7250 | 3.52497 | 0.449991 | 지상 5층 | 레벨 : 지상 5층 | 17500 | 6500 | 17100
7668725 | 지상 5층 | 6950 | 0.1 | 0.65 | 지상 5층 | 레벨 : 지상 5층 | 17500 | 6500 | 17100
7668782 | 지상 6층 | 7250 | 3.52497 | 0.449991 | 지상 6층 | 레벨 : 지상 6층 | 21600 | 6500 | 21200
7668783 | 지상 6층 | 6950 | 0.1 | 0.65 | 지상 6층 | 레벨 : 지상 6층 | 21600 | 6500 | 21200
7668840 | 지상 7층 | 7250 | 3.52497 | 0.449991 | 지상 7층 | 레벨 : 지상 7층 | 25700 | 6500 | 25300
7668841 | 지상 7층 | 6950 | 0.1 | 0.65 | 지상 7층 | 레벨 : 지상 7층 | 25700 | 6500 | 25300
7668898 | 지상 8층 | 7250 | 3.52497 | 0.449991 | 지상 8층 | 레벨 : 지상 8층 | 29800 | 6500 | 29400
7668899 | 지상 8층 | 6950 | 0.1 | 0.65 | 지상 8층 | 레벨 : 지상 8층 | 29800 | 6500 | 29400
7668956 | 지상 9층 | 7250 | 3.52497 | 0.449991 | 지상 9층 | 레벨 : 지상 9층 | 33900 | 6500 | 33500
7668957 | 지상 9층 | 6950 | 0.1 | 0.65 | 지상 9층 | 레벨 : 지상 9층 | 33900 | 6500 | 33500
7669014 | 지상 10층 | 7250 | 3.52497 | 0.449991 | 지상 10층 | 레벨 : 지상 10층 | 38400 | 6500 | 38000 | 구조 - 보강 철근 피복 - 상단 면: 보강 철근 피복 1 <25 mm>
7669015 | 지상 10층 | 6950 | 0.1 | 0.65 | 지상 10층 | 레벨 : 지상 10층 | 38400 | 6500 | 38000

# IfcBeam: BM111-철근콘크리트구조 보:BM110-철근 콘크리트구조 보_400 x 400_2-10G6 (27)
Type - ID 데이터 - 유형 마크: G6; 유형 이름: BM110-철근 콘크리트구조 보_400 x 400_2-10G6
Type - 구조 - 단면 모양: 0
Type - 기타 - 내화구조여부: yes; 주요구조부여부: yes; 카테고리: 구조 프레임; KBIMS-부위코드: E23; 제작정보: bSK-2021_KBIMS2.0-bC; 조달청표준공사코드: AD; 패밀리 이름: BM111-철근콘크리트구조 보
Type - 재료 및 마감재 - 구조 재료: KBIMS-콘크리트
Type - 치수 - 가로치수: 400 mm; 세로치수: 400 mm
Type - Pset_BeamCommon - IsExternal: no; LoadBearing: yes
Material: KBIMS-콘크리트
Pset_BeamCommon - Slope: 0 deg; Reference: BM110-철근 콘크리트구조 보_400 x 400_2-10G6
Pset_QuantityTakeOff - Reference: BM110-철근 콘크리트구조 보_400 x 400_2-10G6; sets with these values: 2
ID 데이터 - 연관 있음: no
공정 - 생성 공정: 새 구성
구속조건 - 끝 레벨 간격띄우기: 0 mm; 단면형상 회전: 0 deg; 방향: 보통; 시작 레벨 간격띄우기: 0 mm
구조 - 보강 철근 피복 - 다른 면: 보강 철근 피복 1 <25 mm>; 보강 철근 피복 - 하단 면: 보강 철근 피복 1 <25 mm>; 시작 부착 유형: 끝 입면; 구조적 용도: 거더; 끝 부착 유형: 끝 입면
기타 - 패밀리: BM111-철근콘크리트구조 보; 유형: BM110-철근 콘크리트구조 보_400 x 400_2-10G6; 유형 ID: 7669419; 패밀리 및 유형: BM111-철근콘크리트구조 보: BM110-철근 콘크리트구조 보_400 x 400_2-10G6
기하학적 위치 - yz 맞춤: 균일; y 간격띄우기 값: 0 mm; y 맞춤: 원점; z 간격띄우기 값: 0 mm; z 맞춤: 상단; 결합 상태: 두 결합 모두 사용
치수 - 단면적: 0.16 m2
Name (BM111-철근콘크리트구조 보:BM110-철근 콘크리트구조 보_400 x 400_2-10G6:...) | In | CrossSectionArea (m2) | NetVolume (m3) = 체적 (m3) | Span (mm) = 길이 (mm) | 참조 레벨 | 작업 기준면 | 참조 레벨 입면도 (mm) = 상단 기준 레벨 (mm) | 절단 길이 (mm) | 하단 기준 레벨 (mm)
7668352 | 지상 2층 | 0.1 | 1.07 | 11850 | 지상 2층 | 레벨 : 지상 2층 | 4800 | 10700 | 4400 | 구조 - 보강 철근 피복 - 상단 면: 보강 철근 피복 1 <25 mm>
7668355 | 지상 2층 | 0.1 | 1.07 | 11800 | 지상 2층 | 레벨 : 지상 2층 | 4800 | 10700 | 4400
7668358 | 지상 2층 | 0.1 | 1.09 | 11900 | 지상 2층 | 레벨 : 지상 2층 | 4800 | 10900 | 4400
7668410 | 지상 3층 | 0.1 | 1.09 | 11850 | 지상 3층 | 레벨 : 지상 3층 | 9300 | 10900 | 8900 | 구조 - 보강 철근 피복 - 상단 면: 보강 철근 피복 1 <25 mm>
7668413 | 지상 3층 | 0.1 | 1.09 | 11800 | 지상 3층 | 레벨 : 지상 3층 | 9300 | 10900 | 8900
7668416 | 지상 3층 | 5.85843 | 0.750547 | 12000 | 지상 3층 | 레벨 : 지상 3층 | 9300 | 10900 | 8900
7668657 | 지상 4층 | 0.1 | 1.09 | 11850 | 지상 4층 | 레벨 : 지상 4층 | 13400 | 10900 | 13000 | 구조 - 보강 철근 피복 - 상단 면: 보강 철근 피복 1 <25 mm>
7668660 | 지상 4층 | 0.1 | 1.09 | 11800 | 지상 4층 | 레벨 : 지상 4층 | 13400 | 10900 | 13000
7668663 | 지상 4층 | 0.1 | 1.09 | 12000 | 지상 4층 | 레벨 : 지상 4층 | 13400 | 10900 | 13000
7668715 | 지상 5층 | 0.1 | 1.09 | 11850 | 지상 5층 | 레벨 : 지상 5층 | 17500 | 10900 | 17100 | 구조 - 보강 철근 피복 - 상단 면: 보강 철근 피복 1 <25 mm>
7668718 | 지상 5층 | 0.1 | 1.09 | 11800 | 지상 5층 | 레벨 : 지상 5층 | 17500 | 10900 | 17100
7668721 | 지상 5층 | 0.1 | 1.09 | 12000 | 지상 5층 | 레벨 : 지상 5층 | 17500 | 10900 | 17100
7668773 | 지상 6층 | 0.1 | 1.09 | 11850 | 지상 6층 | 레벨 : 지상 6층 | 21600 | 10900 | 21200 | 구조 - 보강 철근 피복 - 상단 면: 보강 철근 피복 1 <25 mm>
7668776 | 지상 6층 | 0.1 | 1.09 | 11800 | 지상 6층 | 레벨 : 지상 6층 | 21600 | 10900 | 21200
7668779 | 지상 6층 | 0.1 | 1.09 | 12000 | 지상 6층 | 레벨 : 지상 6층 | 21600 | 10900 | 21200
7668831 | 지상 7층 | 0.1 | 1.09 | 11850 | 지상 7층 | 레벨 : 지상 7층 | 25700 | 10900 | 25300 | 구조 - 보강 철근 피복 - 상단 면: 보강 철근 피복 1 <25 mm>
7668834 | 지상 7층 | 0.1 | 1.09 | 11800 | 지상 7층 | 레벨 : 지상 7층 | 25700 | 10900 | 25300
7668837 | 지상 7층 | 0.1 | 1.09 | 12000 | 지상 7층 | 레벨 : 지상 7층 | 25700 | 10900 | 25300
7668889 | 지상 8층 | 0.1 | 1.09 | 11850 | 지상 8층 | 레벨 : 지상 8층 | 29800 | 10900 | 29400 | 구조 - 보강 철근 피복 - 상단 면: 보강 철근 피복 1 <25 mm>
7668892 | 지상 8층 | 0.1 | 1.09 | 11800 | 지상 8층 | 레벨 : 지상 8층 | 29800 | 10900 | 29400
7668895 | 지상 8층 | 0.1 | 1.09 | 12000 | 지상 8층 | 레벨 : 지상 8층 | 29800 | 10900 | 29400
7668947 | 지상 9층 | 0.1 | 1.11 | 11850 | 지상 9층 | 레벨 : 지상 9층 | 33900 | 11100 | 33500 | 구조 - 보강 철근 피복 - 상단 면: 보강 철근 피복 1 <25 mm>
7668950 | 지상 9층 | 0.1 | 1.11 | 11800 | 지상 9층 | 레벨 : 지상 9층 | 33900 | 11100 | 33500
7668953 | 지상 9층 | 0.1 | 1.11 | 12000 | 지상 9층 | 레벨 : 지상 9층 | 33900 | 11100 | 33500
7669005 | 지상 10층 | 0.1 | 1.11 | 11850 | 지상 10층 | 레벨 : 지상 10층 | 38400 | 11100 | 38000 | 구조 - 보강 철근 피복 - 상단 면: 보강 철근 피복 1 <25 mm>
7669008 | 지상 10층 | 0.1 | 1.11 | 11800 | 지상 10층 | 레벨 : 지상 10층 | 38400 | 11100 | 38000
7669011 | 지상 10층 | 0.1 | 1.11 | 12000 | 지상 10층 | 레벨 : 지상 10층 | 38400 | 11100 | 38000

# IfcBeam: BM111-철근콘크리트구조 보:BM110-철근 콘크리트구조 보_400 x 400_2-10G7 (45)
Type - ID 데이터 - 유형 마크: G7; 유형 이름: BM110-철근 콘크리트구조 보_400 x 400_2-10G7
Type - 구조 - 단면 모양: 0
Type - 기타 - 내화구조여부: yes; 주요구조부여부: yes; 카테고리: 구조 프레임; KBIMS-부위코드: E23; 제작정보: bSK-2021_KBIMS2.0-bC; 조달청표준공사코드: AD; 패밀리 이름: BM111-철근콘크리트구조 보
Type - 재료 및 마감재 - 구조 재료: KBIMS-콘크리트
Type - 치수 - 가로치수: 400 mm; 세로치수: 400 mm
Type - Pset_BeamCommon - IsExternal: no; LoadBearing: yes
Material: KBIMS-콘크리트
Pset_BeamCommon - Slope: 0 deg; Reference: BM110-철근 콘크리트구조 보_400 x 400_2-10G7
Pset_QuantityTakeOff - Reference: BM110-철근 콘크리트구조 보_400 x 400_2-10G7; sets with these values: 2
ID 데이터 - 연관 있음: no
공정 - 생성 공정: 새 구성
구속조건 - 끝 레벨 간격띄우기: 0 mm; 단면형상 회전: 0 deg; 방향: 보통; 시작 레벨 간격띄우기: 0 mm
구조 - 보강 철근 피복 - 다른 면: 보강 철근 피복 1 <25 mm>; 보강 철근 피복 - 하단 면: 보강 철근 피복 1 <25 mm>; 시작 부착 유형: 끝 입면; 끝 부착 유형: 끝 입면
기타 - 패밀리: BM111-철근콘크리트구조 보; 유형: BM110-철근 콘크리트구조 보_400 x 400_2-10G7; 유형 ID: 7669418; 패밀리 및 유형: BM111-철근콘크리트구조 보: BM110-철근 콘크리트구조 보_400 x 400_2-10G7
기하학적 위치 - yz 맞춤: 균일; y 간격띄우기 값: 0 mm; y 맞춤: 원점; z 간격띄우기 값: 0 mm; z 맞춤: 상단; 결합 상태: 두 결합 모두 사용
치수 - 단면적: 0.16 m2
Name (BM111-철근콘크리트구조 보:BM110-철근 콘크리트구조 보_400 x 400_2-10G7:...) | In | CrossSectionArea (m2) | NetVolume (m3) = 체적 (m3) | Span (mm) = 길이 (mm) | 작업 기준면 | 참조 레벨 | 참조 레벨 입면도 (mm) = 상단 기준 레벨 (mm) | 구조적 용도 | 절단 길이 (mm) | 하단 기준 레벨 (mm)
7668338 | 지상 2층 | 0.1 | 1.19 | 12900 | 레벨 : 지상 2층 | 지상 2층 | 4800 | 기타 | 11900 | 4400
7668343 | 지상 2층 | 0.1 | 1.18 | 12850 | 레벨 : 지상 2층 | 지상 2층 | 4800 | 기타 | 11800 | 4400
7668347 | 지상 2층 | 0.1 | 1.17 | 12850 | 레벨 : 지상 2층 | 지상 2층 | 4800 | 기타 | 11700 | 4400
7668376 | 지상 2층 | 0.1 | 1.17 | 13100 | 레벨 : 지상 2층 | 지상 2층 | 4800 | 기타 | 11700 | 4400
7668379 | 지상 2층 | 0.0499999 | 0.589998 | 12249 | 레벨 : 지상 2층 | 지상 2층 | 4800 | 거더 | 11800 | 4400
7668396 | 지상 3층 | 6.34976 | 0.818689 | 12900 | 레벨 : 지상 3층 | 지상 3층 | 9300 | 기타 | 11900 | 8900
7668401 | 지상 3층 | 0.1 | 1.19 | 13000 | 레벨 : 지상 3층 | 지상 3층 | 9300 | 기타 | 11900 | 8900
7668405 | 지상 3층 | 0.1 | 1.19 | 12800 | 레벨 : 지상 3층 | 지상 3층 | 9300 | 기타 | 11900 | 8900
7668434 | 지상 3층 | 0.1 | 1.19 | 13000 | 레벨 : 지상 3층 | 지상 3층 | 9300 | 기타 | 11900 | 8900
7668437 | 지상 3층 | 0.0499999 | 0.594998 | 12249 | 레벨 : 지상 3층 | 지상 3층 | 9300 | 거더 | 11900 | 8900
7668643 | 지상 4층 | 0.1 | 1.19 | 12900 | 레벨 : 지상 4층 | 지상 4층 | 13400 | 기타 | 11900 | 13000
7668648 | 지상 4층 | 0.1 | 1.19 | 13000 | 레벨 : 지상 4층 | 지상 4층 | 13400 | 기타 | 11900 | 13000
7668652 | 지상 4층 | 0.1 | 1.19 | 12800 | 레벨 : 지상 4층 | 지상 4층 | 13400 | 기타 | 11900 | 13000
7668681 | 지상 4층 | 0.1 | 1.19 | 13000 | 레벨 : 지상 4층 | 지상 4층 | 13400 | 기타 | 11900 | 13000
7668684 | 지상 4층 | 0.0499999 | 0.594998 | 12249 | 레벨 : 지상 4층 | 지상 4층 | 13400 | 거더 | 11900 | 13000
7668701 | 지상 5층 | 0.1 | 1.19 | 12900 | 레벨 : 지상 5층 | 지상 5층 | 17500 | 기타 | 11900 | 17100
7668706 | 지상 5층 | 0.1 | 1.19 | 13000 | 레벨 : 지상 5층 | 지상 5층 | 17500 | 기타 | 11900 | 17100
7668710 | 지상 5층 | 0.1 | 1.19 | 12800 | 레벨 : 지상 5층 | 지상 5층 | 17500 | 기타 | 11900 | 17100
7668739 | 지상 5층 | 0.1 | 1.19 | 13000 | 레벨 : 지상 5층 | 지상 5층 | 17500 | 기타 | 11900 | 17100
7668742 | 지상 5층 | 0.0499999 | 0.594998 | 12249 | 레벨 : 지상 5층 | 지상 5층 | 17500 | 거더 | 11900 | 17100
7668759 | 지상 6층 | 0.1 | 1.19 | 12900 | 레벨 : 지상 6층 | 지상 6층 | 21600 | 기타 | 11900 | 21200
7668764 | 지상 6층 | 0.1 | 1.19 | 13000 | 레벨 : 지상 6층 | 지상 6층 | 21600 | 기타 | 11900 | 21200
7668768 | 지상 6층 | 0.1 | 1.19 | 12800 | 레벨 : 지상 6층 | 지상 6층 | 21600 | 기타 | 11900 | 21200
7668797 | 지상 6층 | 0.1 | 1.19 | 13000 | 레벨 : 지상 6층 | 지상 6층 | 21600 | 기타 | 11900 | 21200
7668800 | 지상 6층 | 0.0499999 | 0.594998 | 12249 | 레벨 : 지상 6층 | 지상 6층 | 21600 | 거더 | 11900 | 21200
7668817 | 지상 7층 | 0.1 | 1.19 | 12900 | 레벨 : 지상 7층 | 지상 7층 | 25700 | 기타 | 11900 | 25300
7668822 | 지상 7층 | 0.1 | 1.19 | 13000 | 레벨 : 지상 7층 | 지상 7층 | 25700 | 기타 | 11900 | 25300
7668826 | 지상 7층 | 0.1 | 1.19 | 12800 | 레벨 : 지상 7층 | 지상 7층 | 25700 | 기타 | 11900 | 25300
7668855 | 지상 7층 | 0.1 | 1.19 | 13000 | 레벨 : 지상 7층 | 지상 7층 | 25700 | 기타 | 11900 | 25300
7668858 | 지상 7층 | 0.0499999 | 0.594998 | 12249 | 레벨 : 지상 7층 | 지상 7층 | 25700 | 거더 | 11900 | 25300
7668875 | 지상 8층 | 0.1 | 1.19 | 12900 | 레벨 : 지상 8층 | 지상 8층 | 29800 | 기타 | 11900 | 29400
7668880 | 지상 8층 | 0.1 | 1.19 | 13000 | 레벨 : 지상 8층 | 지상 8층 | 29800 | 기타 | 11900 | 29400
7668884 | 지상 8층 | 0.1 | 1.19 | 12800 | 레벨 : 지상 8층 | 지상 8층 | 29800 | 기타 | 11900 | 29400
7668913 | 지상 8층 | 0.1 | 1.19 | 13000 | 레벨 : 지상 8층 | 지상 8층 | 29800 | 기타 | 11900 | 29400
7668916 | 지상 8층 | 0.0499999 | 0.594998 | 12249 | 레벨 : 지상 8층 | 지상 8층 | 29800 | 거더 | 11900 | 29400
7668933 | 지상 9층 | 0.1 | 1.21 | 12900 | 레벨 : 지상 9층 | 지상 9층 | 33900 | 기타 | 12100 | 33500
7668938 | 지상 9층 | 0.1 | 1.21 | 13000 | 레벨 : 지상 9층 | 지상 9층 | 33900 | 기타 | 12100 | 33500
7668942 | 지상 9층 | 0.1 | 1.21 | 12800 | 레벨 : 지상 9층 | 지상 9층 | 33900 | 기타 | 12100 | 33500
7668971 | 지상 9층 | 0.1 | 1.21 | 13000 | 레벨 : 지상 9층 | 지상 9층 | 33900 | 기타 | 12100 | 33500
7668974 | 지상 9층 | 0.0499999 | 0.604999 | 12650 | 레벨 : 지상 9층 | 지상 9층 | 33900 | 거더 | 12100 | 33500
7668991 | 지상 10층 | 0.1 | 1.21 | 12900 | 레벨 : 지상 10층 | 지상 10층 | 38400 | 기타 | 12100 | 38000
7668996 | 지상 10층 | 0.1 | 1.21 | 13000 | 레벨 : 지상 10층 | 지상 10층 | 38400 | 기타 | 12100 | 38000
7669000 | 지상 10층 | 0.1 | 1.21 | 12800 | 레벨 : 지상 10층 | 지상 10층 | 38400 | 기타 | 12100 | 38000
7669029 | 지상 10층 | 0.1 | 1.21 | 13000 | 레벨 : 지상 10층 | 지상 10층 | 38400 | 기타 | 12100 | 38000
7669032 | 지상 10층 | 0.0499999 | 0.604999 | 12650 | 레벨 : 지상 10층 | 지상 10층 | 38400 | 거더 | 12100 | 38000

# IfcBeam: BM111-철근콘크리트구조 보:BM110-철근 콘크리트구조 보_400 x 400_2-10G8 (27)
Type - ID 데이터 - 유형 마크: G8; 유형 이름: BM110-철근 콘크리트구조 보_400 x 400_2-10G8
Type - 구조 - 단면 모양: 0
Type - 기타 - 내화구조여부: yes; 주요구조부여부: yes; 카테고리: 구조 프레임; KBIMS-부위코드: E23; 제작정보: bSK-2021_KBIMS2.0-bC; 조달청표준공사코드: AD; 패밀리 이름: BM111-철근콘크리트구조 보
Type - 재료 및 마감재 - 구조 재료: KBIMS-콘크리트
Type - 치수 - 가로치수: 400 mm; 세로치수: 400 mm
Type - Pset_BeamCommon - IsExternal: no; LoadBearing: yes
Material: KBIMS-콘크리트
Pset_BeamCommon - Slope: 0 deg; Reference: BM110-철근 콘크리트구조 보_400 x 400_2-10G8
Pset_QuantityTakeOff - Reference: BM110-철근 콘크리트구조 보_400 x 400_2-10G8; sets with these values: 2
ID 데이터 - 연관 있음: no
공정 - 생성 공정: 새 구성
구속조건 - 끝 레벨 간격띄우기: 0 mm; 단면형상 회전: 0 deg; 방향: 보통; 시작 레벨 간격띄우기: 0 mm
구조 - 보강 철근 피복 - 다른 면: 보강 철근 피복 1 <25 mm>; 보강 철근 피복 - 하단 면: 보강 철근 피복 1 <25 mm>; 시작 부착 유형: 끝 입면; 끝 부착 유형: 끝 입면
기타 - 패밀리: BM111-철근콘크리트구조 보; 유형: BM110-철근 콘크리트구조 보_400 x 400_2-10G8; 유형 ID: 7669410; 패밀리 및 유형: BM111-철근콘크리트구조 보: BM110-철근 콘크리트구조 보_400 x 400_2-10G8
기하학적 위치 - yz 맞춤: 균일; y 간격띄우기 값: 0 mm; y 맞춤: 원점; z 간격띄우기 값: 0 mm; z 맞춤: 상단; 결합 상태: 두 결합 모두 사용
치수 - 단면적: 0.16 m2
Name (BM111-철근콘크리트구조 보:BM110-철근 콘크리트구조 보_400 x 400_2-10G8:...) | In | CrossSectionArea (m2) | NetVolume (m3) = 체적 (m3) | Span (mm) = 길이 (mm) | 참조 레벨 | 작업 기준면 | 참조 레벨 입면도 (mm) = 상단 기준 레벨 (mm) | 구조적 용도 | 절단 길이 (mm) | 하단 기준 레벨 (mm)
7668339 | 지상 2층 | 0.1 | 0.25 | 2700 | 지상 2층 | 레벨 : 지상 2층 | 4800 | 기타 | 2500 | 4400
7668344 | 지상 2층 | 0.1 | 0.25 | 3050 | 지상 2층 | 레벨 : 지상 2층 | 4800 | 기타 | 2500 | 4400 | 구조 - 보강 철근 피복 - 상단 면: 보강 철근 피복 1 <25 mm>
7668380 | 지상 2층 | 0.0499999 | 0.104999 | 2549 | 지상 2층 | 레벨 : 지상 2층 | 4800 | 거더 | 2099.98 | 4400
7668397 | 지상 3층 | 0.0687501 | 0.171875 | 3000 | 지상 3층 | 레벨 : 지상 3층 | 9300 | 기타 | 2500 | 8900
7668402 | 지상 3층 | 0.1 | 0.25 | 3300 | 지상 3층 | 레벨 : 지상 3층 | 9300 | 기타 | 2500 | 8900 | 구조 - 보강 철근 피복 - 상단 면: 보강 철근 피복 1 <25 mm>
7668438 | 지상 3층 | 0.0499999 | 0.104999 | 2549 | 지상 3층 | 레벨 : 지상 3층 | 9300 | 거더 | 2099.98 | 8900
7668644 | 지상 4층 | 0.1 | 0.25 | 3000 | 지상 4층 | 레벨 : 지상 4층 | 13400 | 기타 | 2500 | 13000
7668649 | 지상 4층 | 0.1 | 0.25 | 3300 | 지상 4층 | 레벨 : 지상 4층 | 13400 | 기타 | 2500 | 13000 | 구조 - 보강 철근 피복 - 상단 면: 보강 철근 피복 1 <25 mm>
7668685 | 지상 4층 | 0.0499999 | 0.104999 | 2549 | 지상 4층 | 레벨 : 지상 4층 | 13400 | 거더 | 2099.98 | 13000
7668702 | 지상 5층 | 0.1 | 0.25 | 3000 | 지상 5층 | 레벨 : 지상 5층 | 17500 | 기타 | 2500 | 17100
7668707 | 지상 5층 | 0.1 | 0.25 | 3300 | 지상 5층 | 레벨 : 지상 5층 | 17500 | 기타 | 2500 | 17100 | 구조 - 보강 철근 피복 - 상단 면: 보강 철근 피복 1 <25 mm>
7668743 | 지상 5층 | 0.0499999 | 0.104999 | 2549 | 지상 5층 | 레벨 : 지상 5층 | 17500 | 거더 | 2099.98 | 17100
7668760 | 지상 6층 | 0.1 | 0.25 | 3000 | 지상 6층 | 레벨 : 지상 6층 | 21600 | 기타 | 2500 | 21200
7668765 | 지상 6층 | 0.1 | 0.25 | 3300 | 지상 6층 | 레벨 : 지상 6층 | 21600 | 기타 | 2500 | 21200 | 구조 - 보강 철근 피복 - 상단 면: 보강 철근 피복 1 <25 mm>
7668801 | 지상 6층 | 0.0499999 | 0.104999 | 2549 | 지상 6층 | 레벨 : 지상 6층 | 21600 | 거더 | 2099.98 | 21200
7668818 | 지상 7층 | 0.1 | 0.25 | 3000 | 지상 7층 | 레벨 : 지상 7층 | 25700 | 기타 | 2500 | 25300
7668823 | 지상 7층 | 0.1 | 0.25 | 3300 | 지상 7층 | 레벨 : 지상 7층 | 25700 | 기타 | 2500 | 25300 | 구조 - 보강 철근 피복 - 상단 면: 보강 철근 피복 1 <25 mm>
7668859 | 지상 7층 | 0.0499999 | 0.104999 | 2549 | 지상 7층 | 레벨 : 지상 7층 | 25700 | 거더 | 2099.98 | 25300
7668876 | 지상 8층 | 0.1 | 0.25 | 3000 | 지상 8층 | 레벨 : 지상 8층 | 29800 | 기타 | 2500 | 29400
7668881 | 지상 8층 | 0.1 | 0.25 | 3300 | 지상 8층 | 레벨 : 지상 8층 | 29800 | 기타 | 2500 | 29400 | 구조 - 보강 철근 피복 - 상단 면: 보강 철근 피복 1 <25 mm>
7668917 | 지상 8층 | 0.0499999 | 0.104999 | 2549 | 지상 8층 | 레벨 : 지상 8층 | 29800 | 거더 | 2099.98 | 29400
7668934 | 지상 9층 | 0.1 | 0.25 | 3000 | 지상 9층 | 레벨 : 지상 9층 | 33900 | 기타 | 2500 | 33500
7668939 | 지상 9층 | 0.1 | 0.25 | 3300 | 지상 9층 | 레벨 : 지상 9층 | 33900 | 기타 | 2500 | 33500 | 구조 - 보강 철근 피복 - 상단 면: 보강 철근 피복 1 <25 mm>
7668975 | 지상 9층 | 0.0499999 | 0.104999 | 2549 | 지상 9층 | 레벨 : 지상 9층 | 33900 | 거더 | 2099.98 | 33500
7668992 | 지상 10층 | 0.1 | 0.25 | 3000 | 지상 10층 | 레벨 : 지상 10층 | 38400 | 기타 | 2500 | 38000
7668997 | 지상 10층 | 0.1 | 0.25 | 3300 | 지상 10층 | 레벨 : 지상 10층 | 38400 | 기타 | 2500 | 38000 | 구조 - 보강 철근 피복 - 상단 면: 보강 철근 피복 1 <25 mm>
7669033 | 지상 10층 | 0.0799999 | 0.167998 | 2549 | 지상 10층 | 레벨 : 지상 10층 | 38400 | 거더 | 2099.98 | 38000 | 구조 - 보강 철근 피복 - 상단 면: 보강 철근 피복 1 <25 mm>

# IfcBeam: BM111-철근콘크리트구조 보:BM110-철근 콘크리트구조 보_400 x 400_2-10WG1 (2)
In: 지상 2층
Type - PredefinedType: BEAM; Material: KBIMS-콘크리트
Type - ID 데이터 - 유형 마크: WG1; 유형 이름: BM110-철근 콘크리트구조 보_400 x 400_2-10WG1
Type - 구조 - 단면 모양: 0
Type - 기타 - 내화구조여부: yes; 주요구조부여부: yes; 카테고리: 구조 프레임; KBIMS-부위코드: E23; 제작정보: bSK-2021_KBIMS2.0-bC; 조달청표준공사코드: AD; 패밀리 이름: BM111-철근콘크리트구조 보
Type - 재료 및 마감재 - 구조 재료: KBIMS-콘크리트
Type - 치수 - 가로치수: 400 mm; 세로치수: 400 mm
Type - Pset_BeamCommon - IsExternal: no; LoadBearing: yes
Pset_BeamCommon - Slope: 0 deg; Reference: BM110-철근 콘크리트구조 보_400 x 400_2-10WG1
Pset_QuantityTakeOff - Reference: BM110-철근 콘크리트구조 보_400 x 400_2-10WG1; sets with these values: 2
BaseQuantities - CrossSectionArea: 0.000455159 m2
ID 데이터 - 연관 있음: no
공정 - 생성 공정: 새 구성
구속조건 - 끝 레벨 간격띄우기: 0 mm; 단면형상 회전: 0 deg; 방향: 보통; 시작 레벨 간격띄우기: 0 mm; 참조 레벨: 지상 2층; 작업 기준면: 레벨 : 지상 2층; 참조 레벨 입면도: 4800 mm
구조 - 보강 철근 피복 - 다른 면: 보강 철근 피복 1 <25 mm>; 보강 철근 피복 - 하단 면: 보강 철근 피복 1 <25 mm>; 구조적 용도: 기타
기타 - 패밀리: BM111-철근콘크리트구조 보; 유형: BM110-철근 콘크리트구조 보_400 x 400_2-10WG1; 유형 ID: 7669424; 패밀리 및 유형: BM111-철근콘크리트구조 보: BM110-철근 콘크리트구조 보_400 x 400_2-10WG1
기하학적 위치 - yz 맞춤: 균일; y 간격띄우기 값: 0 mm; y 맞춤: 원점; z 간격띄우기 값: 0 mm; z 맞춤: 상단; 결합 상태: 두 결합 모두 사용
치수 - 단면적: 0.16 m2; 상단 기준 레벨: 4800 mm; 하단 기준 레벨: 4400 mm
Name (BM111-철근콘크리트구조 보:BM110-철근 콘크리트구조 보_400 x 400_2-10WG1:...) | Span (mm) = 길이 (mm) | Length (mm) | OuterSurfaceArea (m2) | GrossSurfaceArea (m2) | GrossVolume (m3) | NetVolume (m3) = 체적 (m3) | NetSurfaceArea (m2) | 절단 길이 (mm)
7668382 | 4400 | 2500 | 1.2591 | 1.26001 | 0.0011379 | 0.2 | 5.70091 | 4200
7668383 | 8200 | 5500 | 2.77003 | 2.77094 | 0.00250337 | 0.399818 | 11.0995 | 8000

# IfcBeam: BM111-철근콘크리트구조 보:BM110-철근 콘크리트구조 보_400 x 400_2-10WG1 (25)
Type - PredefinedType: BEAM; Material: KBIMS-콘크리트 (3)
Type - ID 데이터 - 유형 마크: WG1; 유형 이름: BM110-철근 콘크리트구조 보_400 x 400_2-10WG1
Type - 구조 - 단면 모양: 0
Type - 기타 - 내화구조여부: yes; 주요구조부여부: yes; 카테고리: 구조 프레임; KBIMS-부위코드: E23; 제작정보: bSK-2021_KBIMS2.0-bC; 조달청표준공사코드: AD; 패밀리 이름: BM111-철근콘크리트구조 보
Type - 재료 및 마감재 - 구조 재료: KBIMS-콘크리트
Type - 치수 - 가로치수: 400 mm; 세로치수: 400 mm
Type - Pset_BeamCommon - IsExternal: no; LoadBearing: yes
Pset_BeamCommon - Slope: 0 deg; Reference: BM110-철근 콘크리트구조 보_400 x 400_2-10WG1
Pset_QuantityTakeOff - Reference: BM110-철근 콘크리트구조 보_400 x 400_2-10WG1; sets with these values: 2
ID 데이터 - 연관 있음: no
공정 - 생성 공정: 새 구성
구속조건 - 끝 레벨 간격띄우기: 0 mm; 단면형상 회전: 0 deg; 방향: 보통; 시작 레벨 간격띄우기: 0 mm
구조 - 보강 철근 피복 - 다른 면: 보강 철근 피복 1 <25 mm>; 보강 철근 피복 - 하단 면: 보강 철근 피복 1 <25 mm>; 구조적 용도: 기타
기타 - 패밀리: BM111-철근콘크리트구조 보; 유형: BM110-철근 콘크리트구조 보_400 x 400_2-10WG1; 유형 ID: 7669424; 패밀리 및 유형: BM111-철근콘크리트구조 보: BM110-철근 콘크리트구조 보_400 x 400_2-10WG1
기하학적 위치 - yz 맞춤: 균일; y 간격띄우기 값: 0 mm; y 맞춤: 원점; z 간격띄우기 값: 0 mm; z 맞춤: 상단; 결합 상태: 두 결합 모두 사용
치수 - 단면적: 0.16 m2
Name (BM111-철근콘크리트구조 보:BM110-철근 콘크리트구조 보_400 x 400_2-10WG1:...) | In | Span (mm) = 길이 (mm) | CrossSectionArea (m2) | NetVolume (m3) = 체적 (m3) | 참조 레벨 | 작업 기준면 | 참조 레벨 입면도 (mm) = 상단 기준 레벨 (mm) | 절단 길이 (mm) | 하단 기준 레벨 (mm) | Material
7668381 | 지상 2층 | 10900 | 6.82069 | 0.654322 | 지상 2층 | 레벨 : 지상 2층 | 4800 | 10900 | 4400 | BaseQuantities - NetSurfaceArea: 13.6414 m2
7668439 | 지상 3층 | 10900 | 6.82059 | 0.654414 | 지상 3층 | 레벨 : 지상 3층 | 9300 | 10900 | 8900 | BaseQuantities - NetSurfaceArea: 13.6412 m2
7668440 | 지상 3층 | 4400 | 0.0500043 | 0.200017 | 지상 3층 | 레벨 : 지상 3층 | 9300 | 4000 | 8900 | KBIMS-콘크리트
7668441 | 지상 3층 | 8200 | 0.0500043 | 0.400035 | 지상 3층 | 레벨 : 지상 3층 | 9300 | 8000 | 8900 | KBIMS-콘크리트
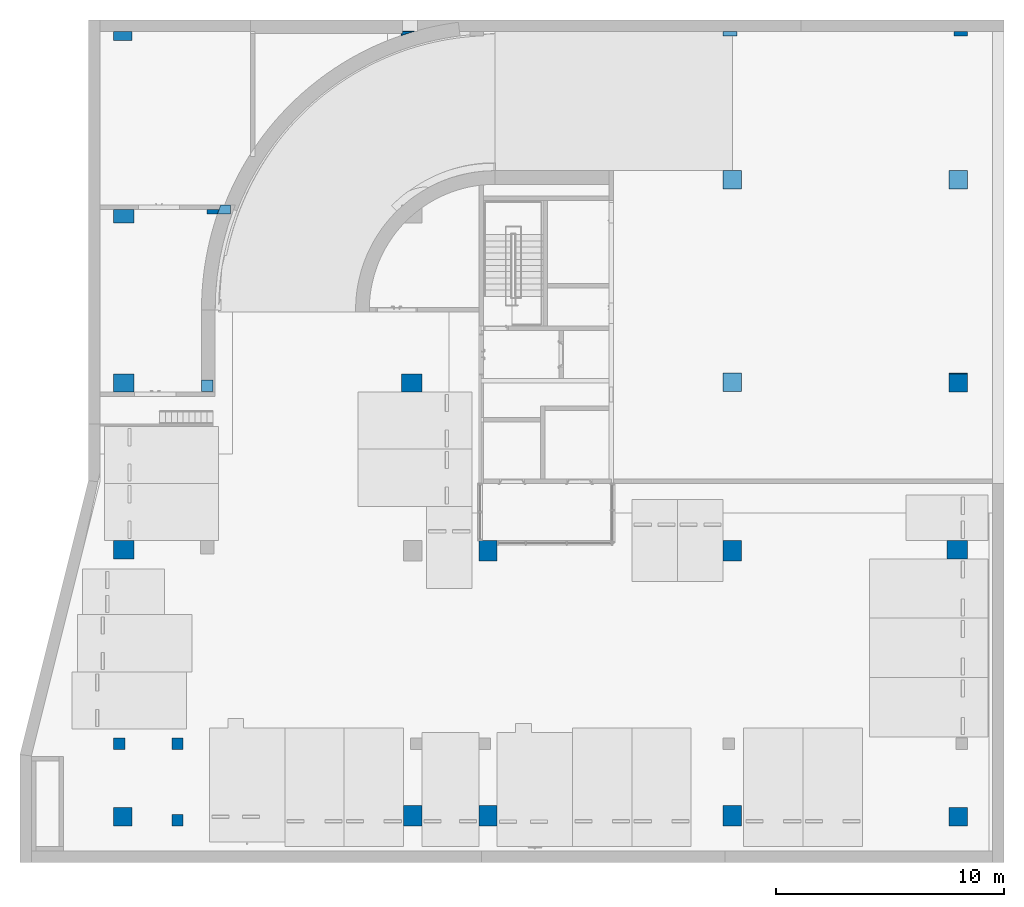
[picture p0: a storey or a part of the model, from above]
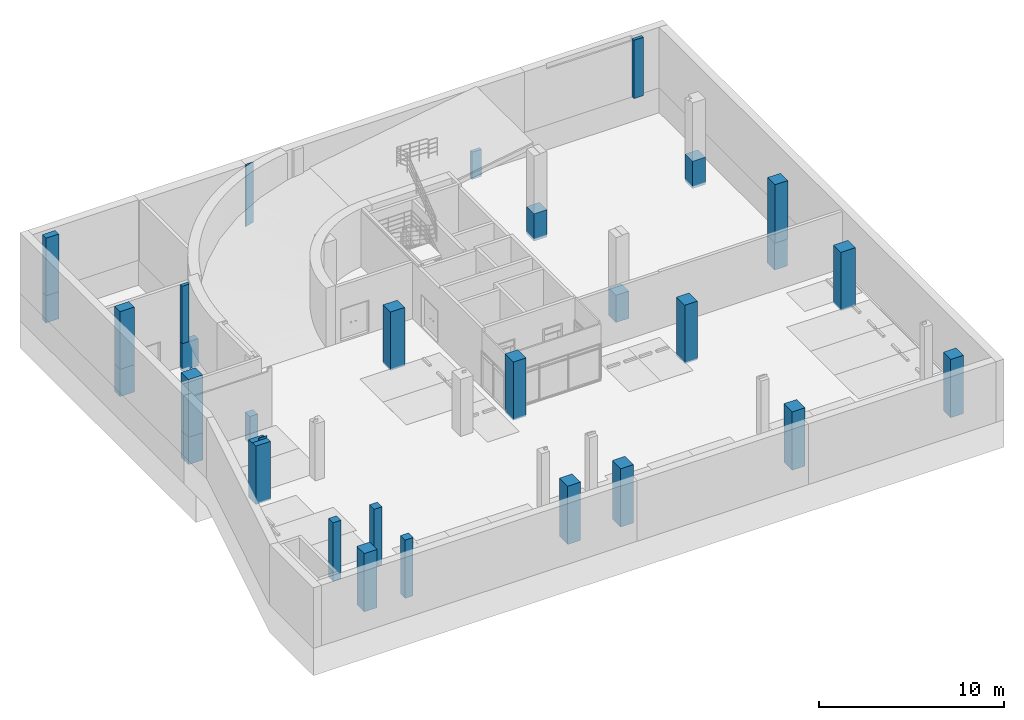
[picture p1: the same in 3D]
Properties of the parts of a building model (IFC2X3), part 7 of 39

# IfcBeam: BM111-철근콘크리트구조 보:BM110-철근 콘크리트구조 보_400 x 400_2-10WG1 (25)
Name (BM111-철근콘크리트구조 보:BM110-철근 콘크리트구조 보_400 x 400_2-10WG1:...) | In | Span (mm) = 길이 (mm) | CrossSectionArea (m2) | NetVolume (m3) = 체적 (m3) | 참조 레벨 | 작업 기준면 | 참조 레벨 입면도 (mm) = 상단 기준 레벨 (mm) | 절단 길이 (mm) | 하단 기준 레벨 (mm) | Material
7668686 | 지상 4층 | 10900 | 5.40995 | 0.646238 | 지상 4층 | 레벨 : 지상 4층 | 13400 | 10900 | 13000 | KBIMS-콘크리트
7668687 | 지상 4층 | 4412 | 2.00563 | 0.212414 | 지상 4층 | 레벨 : 지상 4층 | 13400 | 4223.91 | 13000 | KBIMS-콘크리트
7668688 | 지상 4층 | 8200 | 0.0500043 | 0.400035 | 지상 4층 | 레벨 : 지상 4층 | 13400 | 8000 | 13000 | KBIMS-콘크리트
7668744 | 지상 5층 | 10900 | 5.49552 | 0.655134 | 지상 5층 | 레벨 : 지상 5층 | 17500 | 10900 | 17100 | KBIMS-콘크리트
7668745 | 지상 5층 | 4400 | 0.0500043 | 0.200017 | 지상 5층 | 레벨 : 지상 5층 | 17500 | 4000 | 17100 | KBIMS-콘크리트
7668746 | 지상 5층 | 8200 | 0.0500043 | 0.400035 | 지상 5층 | 레벨 : 지상 5층 | 17500 | 8000 | 17100 | KBIMS-콘크리트
7668802 | 지상 6층 | 10900 | 6.82059 | 0.654414 | 지상 6층 | 레벨 : 지상 6층 | 21600 | 10900 | 21200 | BaseQuantities - NetSurfaceArea: 13.6412 m2
7668803 | 지상 6층 | 4400 | 0.0500043 | 0.200017 | 지상 6층 | 레벨 : 지상 6층 | 21600 | 4000 | 21200 | KBIMS-콘크리트
7668804 | 지상 6층 | 8200 | 0.0500043 | 0.400035 | 지상 6층 | 레벨 : 지상 6층 | 21600 | 8000 | 21200 | KBIMS-콘크리트
7668860 | 지상 7층 | 10900 | 6.82059 | 0.654414 | 지상 7층 | 레벨 : 지상 7층 | 25700 | 10900 | 25300 | BaseQuantities - NetSurfaceArea: 13.6412 m2
7668861 | 지상 7층 | 4400 | 0.0500043 | 0.200017 | 지상 7층 | 레벨 : 지상 7층 | 25700 | 4000 | 25300 | KBIMS-콘크리트
7668862 | 지상 7층 | 8200 | 0.0500043 | 0.400035 | 지상 7층 | 레벨 : 지상 7층 | 25700 | 8000 | 25300 | KBIMS-콘크리트
7668918 | 지상 8층 | 10900 | 6.82059 | 0.654414 | 지상 8층 | 레벨 : 지상 8층 | 29800 | 10900 | 29400 | BaseQuantities - NetSurfaceArea: 13.6412 m2
7668919 | 지상 8층 | 4400 | 0.0500043 | 0.200017 | 지상 8층 | 레벨 : 지상 8층 | 29800 | 4000 | 29400 | KBIMS-콘크리트
7668920 | 지상 8층 | 8200 | 0.0500043 | 0.400035 | 지상 8층 | 레벨 : 지상 8층 | 29800 | 8000 | 29400 | KBIMS-콘크리트
7668976 | 지상 9층 | 10900 | 6.82059 | 0.654414 | 지상 9층 | 레벨 : 지상 9층 | 33900 | 10900 | 33500 | BaseQuantities - NetSurfaceArea: 13.6412 m2
7668977 | 지상 9층 | 4400 | 0.0500043 | 0.200017 | 지상 9층 | 레벨 : 지상 9층 | 33900 | 4000 | 33500 | KBIMS-콘크리트
7668978 | 지상 9층 | 8200 | 0.0500043 | 0.400035 | 지상 9층 | 레벨 : 지상 9층 | 33900 | 8000 | 33500 | KBIMS-콘크리트
7669034 | 지상 10층 | 10900 | 6.82059 | 0.654414 | 지상 10층 | 레벨 : 지상 10층 | 38400 | 10900 | 38000 | BaseQuantities - NetSurfaceArea: 13.6412 m2
7669035 | 지상 10층 | 4400 | 0.0500043 | 0.200017 | 지상 10층 | 레벨 : 지상 10층 | 38400 | 4000 | 38000 | KBIMS-콘크리트
7669036 | 지상 10층 | 8200 | 0.0500043 | 0.400035 | 지상 10층 | 레벨 : 지상 10층 | 38400 | 8000 | 38000 | KBIMS-콘크리트

# IfcBeam: BM111-철근콘크리트구조 보:BM110-철근 콘크리트구조 보_400 x 400_2-10WG2 (9)
Type - PredefinedType: BEAM; Material: KBIMS-콘크리트
Type - ID 데이터 - 유형 마크: WG2; 유형 이름: BM110-철근 콘크리트구조 보_400 x 400_2-10WG2
Type - 구조 - 단면 모양: 0
Type - 기타 - 내화구조여부: yes; 주요구조부여부: yes; 카테고리: 구조 프레임; KBIMS-부위코드: E23; 제작정보: bSK-2021_KBIMS2.0-bC; 조달청표준공사코드: AD; 패밀리 이름: BM111-철근콘크리트구조 보
Type - 재료 및 마감재 - 구조 재료: KBIMS-콘크리트
Type - 치수 - 가로치수: 400 mm; 세로치수: 400 mm
Type - Pset_BeamCommon - IsExternal: no; LoadBearing: yes
Pset_BeamCommon - Slope: 0 deg; Reference: BM110-철근 콘크리트구조 보_400 x 400_2-10WG2; Span: 8000 mm
Pset_QuantityTakeOff - Reference: BM110-철근 콘크리트구조 보_400 x 400_2-10WG2; sets with these values: 2
BaseQuantities - Length: 3199.99 mm
ID 데이터 - 연관 있음: no
공정 - 생성 공정: 새 구성
구속조건 - 끝 레벨 간격띄우기: 0 mm; 단면형상 회전: 0 deg; 방향: 보통; 시작 레벨 간격띄우기: 0 mm
구조 - 보강 철근 피복 - 다른 면: 보강 철근 피복 1 <25 mm>; 보강 철근 피복 - 상단 면: 보강 철근 피복 1 <25 mm>; 보강 철근 피복 - 하단 면: 보강 철근 피복 1 <25 mm>; 구조적 용도: 기타
기타 - 패밀리: BM111-철근콘크리트구조 보; 유형: BM110-철근 콘크리트구조 보_400 x 400_2-10WG2; 유형 ID: 7669412; 패밀리 및 유형: BM111-철근콘크리트구조 보: BM110-철근 콘크리트구조 보_400 x 400_2-10WG2
기하학적 위치 - yz 맞춤: 균일; y 간격띄우기 값: 0 mm; y 맞춤: 원점; z 간격띄우기 값: 0 mm; z 맞춤: 상단; 결합 상태: 두 결합 모두 사용
치수 - 길이: 8000 mm; 단면적: 0.16 m2
Name (BM111-철근콘크리트구조 보:BM110-철근 콘크리트구조 보_400 x 400_2-10WG2:...) | In | CrossSectionArea (m2) | OuterSurfaceArea (m2) | GrossSurfaceArea (m2) | GrossVolume (m3) | NetVolume (m3) = 체적 (m3) | NetSurfaceArea (m2) | 참조 레벨 | 작업 기준면 | 참조 레벨 입면도 (mm) = 상단 기준 레벨 (mm) | 절단 길이 (mm) | 하단 기준 레벨 (mm)
7668386 | 지상 2층 | 0.04 | 2.55999 | 2.63999 | 0.128 | 0.518001 | 9.69002 | 지상 2층 | 레벨 : 지상 2층 | 4800 | 7700.02 | 4400
7668444 | 지상 3층 | 0.04 | 2.55999 | 2.63999 | 0.128 | 0.518001 | 9.69002 | 지상 3층 | 레벨 : 지상 3층 | 9300 | 7700.02 | 8900
7668691 | 지상 4층 | 0.04 | 2.55999 | 2.63999 | 0.128 | 0.498 | 9.42999 | 지상 4층 | 레벨 : 지상 4층 | 13400 | 7500 | 13000
7668749 | 지상 5층 | 0.04 | 2.55999 | 2.63999 | 0.128 | 0.498 | 9.42999 | 지상 5층 | 레벨 : 지상 5층 | 17500 | 7500 | 17100
7668807 | 지상 6층 | 0.04 | 2.55999 | 2.63999 | 0.128 | 0.498 | 9.42999 | 지상 6층 | 레벨 : 지상 6층 | 21600 | 7500 | 21200
7668865 | 지상 7층 | 0.04 | 2.55999 | 2.63999 | 0.128 | 0.518001 | 9.69002 | 지상 7층 | 레벨 : 지상 7층 | 25700 | 7700.02 | 25300
7668923 | 지상 8층 | 0.04 | 2.55999 | 2.63999 | 0.128 | 0.518001 | 9.69002 | 지상 8층 | 레벨 : 지상 8층 | 29800 | 7700.02 | 29400
7668981 | 지상 9층 | 0.04 | 2.55999 | 2.63999 | 0.128 | 0.518001 | 9.69002 | 지상 9층 | 레벨 : 지상 9층 | 33900 | 7700.02 | 33500
7669039 | 지상 10층 | 0.048 | 2.81599 | 2.91199 | 0.153599 | 0.4916 | 8.082 | 지상 10층 | 레벨 : 지상 10층 | 38400 | 7500 | 38000

# IfcBeam: BM111-철근콘크리트구조 보:BM110-철근 콘크리트구조 보_400 x 400_2-10WG2 (9)
Type - ID 데이터 - 유형 마크: WG2; 유형 이름: BM110-철근 콘크리트구조 보_400 x 400_2-10WG2
Type - 구조 - 단면 모양: 0
Type - 기타 - 내화구조여부: yes; 주요구조부여부: yes; 카테고리: 구조 프레임; KBIMS-부위코드: E23; 제작정보: bSK-2021_KBIMS2.0-bC; 조달청표준공사코드: AD; 패밀리 이름: BM111-철근콘크리트구조 보
Type - 재료 및 마감재 - 구조 재료: KBIMS-콘크리트
Type - 치수 - 가로치수: 400 mm; 세로치수: 400 mm
Type - Pset_BeamCommon - IsExternal: no; LoadBearing: yes
Material: KBIMS-콘크리트
Pset_BeamCommon - Slope: 0 deg; Reference: BM110-철근 콘크리트구조 보_400 x 400_2-10WG2; Span: 6900 mm
Pset_QuantityTakeOff - Reference: BM110-철근 콘크리트구조 보_400 x 400_2-10WG2; sets with these values: 2
ID 데이터 - 연관 있음: no
공정 - 생성 공정: 새 구성
구속조건 - 끝 레벨 간격띄우기: 0 mm; 단면형상 회전: 0 deg; 방향: 보통; 시작 레벨 간격띄우기: 0 mm
구조 - 보강 철근 피복 - 다른 면: 보강 철근 피복 1 <25 mm>; 보강 철근 피복 - 하단 면: 보강 철근 피복 1 <25 mm>; 구조적 용도: 기타; 절단 길이: 6500 mm
기타 - 패밀리: BM111-철근콘크리트구조 보; 유형: BM110-철근 콘크리트구조 보_400 x 400_2-10WG2; 유형 ID: 7669412; 패밀리 및 유형: BM111-철근콘크리트구조 보: BM110-철근 콘크리트구조 보_400 x 400_2-10WG2
기하학적 위치 - yz 맞춤: 균일; y 간격띄우기 값: 0 mm; y 맞춤: 원점; z 간격띄우기 값: 0 mm; z 맞춤: 상단; 결합 상태: 두 결합 모두 사용
치수 - 길이: 6900 mm; 단면적: 0.16 m2
Name (BM111-철근콘크리트구조 보:BM110-철근 콘크리트구조 보_400 x 400_2-10WG2:...) | In | CrossSectionArea (m2) | NetVolume (m3) = 체적 (m3) | 참조 레벨 | 작업 기준면 | 참조 레벨 입면도 (mm) = 상단 기준 레벨 (mm) | 하단 기준 레벨 (mm)
7668384 | 지상 2층 | 0.0499957 | 0.324972 | 지상 2층 | 레벨 : 지상 2층 | 4800 | 4400
7668442 | 지상 3층 | 0.0499957 | 0.324972 | 지상 3층 | 레벨 : 지상 3층 | 9300 | 8900
7668689 | 지상 4층 | 0.0499957 | 0.324972 | 지상 4층 | 레벨 : 지상 4층 | 13400 | 13000
7668747 | 지상 5층 | 0.0499957 | 0.324972 | 지상 5층 | 레벨 : 지상 5층 | 17500 | 17100
7668805 | 지상 6층 | 0.0499935 | 0.324958 | 지상 6층 | 레벨 : 지상 6층 | 21600 | 21200
7668863 | 지상 7층 | 0.0499935 | 0.324958 | 지상 7층 | 레벨 : 지상 7층 | 25700 | 25300
7668921 | 지상 8층 | 0.0499935 | 0.324958 | 지상 8층 | 레벨 : 지상 8층 | 29800 | 29400
7668979 | 지상 9층 | 0.0499935 | 0.324958 | 지상 9층 | 레벨 : 지상 9층 | 33900 | 33500
7669037 | 지상 10층 | 0.0499935 | 0.324958 | 지상 10층 | 레벨 : 지상 10층 | 38400 | 38000

# IfcBeam: BM111-철근콘크리트구조 보:BM110-철근 콘크리트구조 보_400 x 500_1G7(역보) (2)
In: 지상 1층
Type - ID 데이터 - 유형 마크: G7; 유형 이름: BM110-철근 콘크리트구조 보_400 x 500_1G7(역보)
Type - 구조 - 단면 모양: 0
Type - 기타 - 내화구조여부: yes; 주요구조부여부: yes; 카테고리: 구조 프레임; KBIMS-부위코드: E23; 제작정보: bSK-2021_KBIMS2.0-bC; 조달청표준공사코드: AD; 패밀리 이름: BM111-철근콘크리트구조 보
Type - 재료 및 마감재 - 구조 재료: KBIMS-콘크리트
Type - 치수 - 가로치수: 400 mm; 세로치수: 500 mm
Type - Pset_BeamCommon - IsExternal: no; LoadBearing: yes
Material: KBIMS-콘크리트
Pset_BeamCommon - Slope: 0 deg; Reference: BM110-철근 콘크리트구조 보_400 x 500_1G7(역보); Span: 6300 mm
Pset_QuantityTakeOff - Reference: BM110-철근 콘크리트구조 보_400 x 500_1G7(역보); sets with these values: 2
ID 데이터 - 연관 있음: no
공정 - 생성 공정: 새 구성
구속조건 - 단면형상 회전: 0 deg; 참조 레벨: 지상 1층; 참조 레벨 입면도: 0 mm; 끝 레벨 간격띄우기: 500 mm; 시작 레벨 간격띄우기: 500 mm
구조 - 보강 철근 피복 - 다른 면: 보강 철근 피복 1 <25 mm>; 보강 철근 피복 - 하단 면: 보강 철근 피복 1 <25 mm>; 구조적 용도: 거더
기타 - 패밀리: BM111-철근콘크리트구조 보; 유형: BM110-철근 콘크리트구조 보_400 x 500_1G7(역보); 유형 ID: 7667207; 패밀리 및 유형: BM111-철근콘크리트구조 보: BM110-철근 콘크리트구조 보_400 x 500_1G7(역보)
기하학적 위치 - yz 맞춤: 균일; y 간격띄우기 값: 0 mm; y 맞춤: 원점; z 간격띄우기 값: 0 mm; z 맞춤: 상단; 결합 상태: 하나 또는 두 개의 결합 사용 안 함
치수 - 하단 기준 레벨: 0 mm; 길이: 6300 mm; 단면적: 0.2 m2; 상단 기준 레벨: 500 mm
Name (BM111-철근콘크리트구조 보:BM110-철근 콘크리트구조 보_400 x 500_1G7(역보):...) | CrossSectionArea (m2) | NetVolume (m3) = 체적 (m3) | 절단 길이 (mm)
7667197 | 0.12 | 0.694371 | 5786.42
7669274 | 2.41134 | 0.144372 | 5900.29 | 구조 - 보강 철근 피복 - 상단 면: 보강 철근 피복 1 <25 mm>

# IfcBeam: BM111-철근콘크리트구조 보:BM110-철근 콘크리트구조 보_400 x 500_RB1 (3)
In: 옥탑층
Type - ID 데이터 - 유형 마크: B1; 유형 이름: BM110-철근 콘크리트구조 보_400 x 500_RB1
Type - 구조 - 단면 모양: 0
Type - 기타 - 내화구조여부: yes; 주요구조부여부: yes; 카테고리: 구조 프레임; KBIMS-부위코드: E23; 제작정보: bSK-2021_KBIMS2.0-bC; 조달청표준공사코드: AD; 패밀리 이름: BM111-철근콘크리트구조 보
Type - 재료 및 마감재 - 구조 재료: KBIMS-콘크리트
Type - 치수 - 가로치수: 400 mm; 세로치수: 500 mm
Type - Pset_BeamCommon - IsExternal: no; LoadBearing: yes
Material: KBIMS-콘크리트
BaseQuantities - CrossSectionArea: 0.14 m2
Pset_BeamCommon - Slope: 0 deg; Reference: BM110-철근 콘크리트구조 보_400 x 500_RB1
Pset_QuantityTakeOff - Reference: BM110-철근 콘크리트구조 보_400 x 500_RB1; sets with these values: 2
ID 데이터 - 연관 있음: no
공정 - 생성 공정: 새 구성
구속조건 - 끝 레벨 간격띄우기: 0 mm; 단면형상 회전: 0 deg; 방향: 보통; 시작 레벨 간격띄우기: 0 mm; 참조 레벨: 옥탑층; 작업 기준면: 레벨 : 옥탑층; 참조 레벨 입면도: 43400 mm
구조 - 보강 철근 피복 - 다른 면: 보강 철근 피복 1 <25 mm>; 보강 철근 피복 - 하단 면: 보강 철근 피복 1 <25 mm>; 구조적 용도: 기타
기타 - 패밀리: BM111-철근콘크리트구조 보; 유형: BM110-철근 콘크리트구조 보_400 x 500_RB1; 유형 ID: 7669440; 패밀리 및 유형: BM111-철근콘크리트구조 보: BM110-철근 콘크리트구조 보_400 x 500_RB1
기하학적 위치 - yz 맞춤: 균일; y 간격띄우기 값: 0 mm; y 맞춤: 원점; z 간격띄우기 값: 0 mm; z 맞춤: 상단; 결합 상태: 두 결합 모두 사용
치수 - 단면적: 0.2 m2; 상단 기준 레벨: 43400 mm; 하단 기준 레벨: 42900 mm
Name (BM111-철근콘크리트구조 보:BM110-철근 콘크리트구조 보_400 x 500_RB1:...) | NetVolume (m3) = 체적 (m3) | Span (mm) = 길이 (mm) | 절단 길이 (mm)
7669082 | 1.386 | 10300 | 9900
7669088 | 1.358 | 10200 | 9699.98
7669089 | 1.358 | 10200 | 9699.98

# IfcBeam: BM111-철근콘크리트구조 보:BM110-철근 콘크리트구조 보_400 x 500_RB2 (4)
In: 옥탑층
Type - ID 데이터 - 유형 마크: B2; 유형 이름: BM110-철근 콘크리트구조 보_400 x 500_RB2
Type - 구조 - 단면 모양: 0
Type - 기타 - 내화구조여부: yes; 주요구조부여부: yes; 카테고리: 구조 프레임; KBIMS-부위코드: E23; 제작정보: bSK-2021_KBIMS2.0-bC; 조달청표준공사코드: AD; 패밀리 이름: BM111-철근콘크리트구조 보
Type - 재료 및 마감재 - 구조 재료: KBIMS-콘크리트
Type - 치수 - 가로치수: 400 mm; 세로치수: 500 mm
Type - Pset_BeamCommon - IsExternal: no; LoadBearing: yes
Material: KBIMS-콘크리트
BaseQuantities - CrossSectionArea: 0.14 m2
Pset_BeamCommon - Slope: 0 deg; Reference: BM110-철근 콘크리트구조 보_400 x 500_RB2
Pset_QuantityTakeOff - Reference: BM110-철근 콘크리트구조 보_400 x 500_RB2; sets with these values: 2
ID 데이터 - 연관 있음: no
공정 - 생성 공정: 새 구성
구속조건 - 끝 레벨 간격띄우기: 0 mm; 단면형상 회전: 0 deg; 방향: 보통; 시작 레벨 간격띄우기: 0 mm; 참조 레벨: 옥탑층; 작업 기준면: 레벨 : 옥탑층; 참조 레벨 입면도: 43400 mm
구조 - 보강 철근 피복 - 다른 면: 보강 철근 피복 1 <25 mm>; 보강 철근 피복 - 하단 면: 보강 철근 피복 1 <25 mm>; 구조적 용도: 거더
기타 - 패밀리: BM111-철근콘크리트구조 보; 유형: BM110-철근 콘크리트구조 보_400 x 500_RB2; 유형 ID: 7669445; 패밀리 및 유형: BM111-철근콘크리트구조 보: BM110-철근 콘크리트구조 보_400 x 500_RB2
기하학적 위치 - yz 맞춤: 균일; y 간격띄우기 값: 0 mm; y 맞춤: 원점; z 간격띄우기 값: 0 mm; z 맞춤: 상단; 결합 상태: 두 결합 모두 사용
치수 - 단면적: 0.2 m2; 상단 기준 레벨: 43400 mm; 하단 기준 레벨: 42900 mm
Name (BM111-철근콘크리트구조 보:BM110-철근 콘크리트구조 보_400 x 500_RB2:...) | NetVolume (m3) = 체적 (m3) | Span (mm) = 길이 (mm) | 절단 길이 (mm)
7669072 | 1.61 | 12000 | 11500
7669073 | 1.61 | 12000 | 11500
7669075 | 1.617 | 12050 | 11550
7669076 | 1.617 | 12050 | 11550

# IfcBeam: BM111-철근콘크리트구조 보:BM110-철근 콘크리트구조 보_400 x 500_RB3 (8)
In: 옥탑층
Type - ID 데이터 - 유형 마크: B3; 유형 이름: BM110-철근 콘크리트구조 보_400 x 500_RB3
Type - 구조 - 단면 모양: 0
Type - 기타 - 내화구조여부: yes; 주요구조부여부: yes; 카테고리: 구조 프레임; KBIMS-부위코드: E23; 제작정보: bSK-2021_KBIMS2.0-bC; 조달청표준공사코드: AD; 패밀리 이름: BM111-철근콘크리트구조 보
Type - 재료 및 마감재 - 구조 재료: KBIMS-콘크리트
Type - 치수 - 가로치수: 400 mm; 세로치수: 500 mm
Type - Pset_BeamCommon - IsExternal: no; LoadBearing: yes
Material: KBIMS-콘크리트
BaseQuantities - CrossSectionArea: 0.14 m2
Pset_BeamCommon - Slope: 0 deg; Reference: BM110-철근 콘크리트구조 보_400 x 500_RB3
Pset_QuantityTakeOff - Reference: BM110-철근 콘크리트구조 보_400 x 500_RB3; sets with these values: 2
ID 데이터 - 연관 있음: no
공정 - 생성 공정: 새 구성
구속조건 - 끝 레벨 간격띄우기: 0 mm; 단면형상 회전: 0 deg; 방향: 보통; 시작 레벨 간격띄우기: 0 mm; 참조 레벨: 옥탑층; 작업 기준면: 레벨 : 옥탑층; 참조 레벨 입면도: 43400 mm
구조 - 보강 철근 피복 - 다른 면: 보강 철근 피복 1 <25 mm>; 보강 철근 피복 - 하단 면: 보강 철근 피복 1 <25 mm>; 구조적 용도: 기타
기타 - 패밀리: BM111-철근콘크리트구조 보; 유형: BM110-철근 콘크리트구조 보_400 x 500_RB3; 유형 ID: 7669447; 패밀리 및 유형: BM111-철근콘크리트구조 보: BM110-철근 콘크리트구조 보_400 x 500_RB3
기하학적 위치 - yz 맞춤: 균일; y 간격띄우기 값: 0 mm; y 맞춤: 원점; z 간격띄우기 값: 0 mm; z 맞춤: 상단; 결합 상태: 두 결합 모두 사용
치수 - 단면적: 0.2 m2; 상단 기준 레벨: 43400 mm; 하단 기준 레벨: 42900 mm
Name (BM111-철근콘크리트구조 보:BM110-철근 콘크리트구조 보_400 x 500_RB3:...) | NetVolume (m3) = 체적 (m3) | Span (mm) = 길이 (mm) | 절단 길이 (mm)
7669061 | 1.736 | 13000 | 12400
7669083 | 1.757 | 13050 | 12550
7669092 | 1.75701 | 13050 | 12550.1
7669093 | 1.75701 | 13050 | 12550.1
7669108 | 1.736 | 13000 | 12400
7669109 | 1.736 | 13000 | 12400
7669110 | 1.75701 | 13050 | 12550.1
7669111 | 1.75701 | 13050 | 12550.1

# IfcBeam: BM111-철근콘크리트구조 보:BM110-철근 콘크리트구조 보_400 x 500_RB4, BM111-철근콘크리트구조 보:BM110-철근 콘크리트구조 보_400 x 500_RB4:7669106
In: 옥탑층
Type - PredefinedType: BEAM; Material: KBIMS-콘크리트
Type - ID 데이터 - 유형 마크: B4; 유형 이름: BM110-철근 콘크리트구조 보_400 x 500_RB4
Type - 구조 - 단면 모양: 0
Type - 기타 - 내화구조여부: yes; 주요구조부여부: yes; 카테고리: 구조 프레임; KBIMS-부위코드: E23; 제작정보: bSK-2021_KBIMS2.0-bC; 조달청표준공사코드: AD; 패밀리 이름: BM111-철근콘크리트구조 보
Type - 재료 및 마감재 - 구조 재료: KBIMS-콘크리트
Type - 치수 - 가로치수: 400 mm; 세로치수: 500 mm
Type - Pset_BeamCommon - IsExternal: no; LoadBearing: yes
Pset_BeamCommon - Slope: 0 deg; Reference: BM110-철근 콘크리트구조 보_400 x 500_RB4; Span: 5500 mm
Pset_QuantityTakeOff - Reference: BM110-철근 콘크리트구조 보_400 x 500_RB4; sets with these values: 2
BaseQuantities - Length: 700 mm; CrossSectionArea: 0.077 m2; OuterSurfaceArea: 0.798 m2; GrossSurfaceArea: 0.952 m2; GrossVolume: 0.0539 m3; NetVolume: 0.458768 m3; NetSurfaceArea: 6.33433 m2
ID 데이터 - 연관 있음: no
공정 - 생성 공정: 새 구성
구속조건 - 끝 레벨 간격띄우기: 0 mm; 단면형상 회전: 0 deg; 방향: 보통; 시작 레벨 간격띄우기: 0 mm; 참조 레벨: 옥탑층; 작업 기준면: 레벨 : 옥탑층; 참조 레벨 입면도: 43400 mm
구조 - 보강 철근 피복 - 다른 면: 보강 철근 피복 1 <25 mm>; 보강 철근 피복 - 하단 면: 보강 철근 피복 1 <25 mm>; 구조적 용도: 기타; 절단 길이: 5100 mm
기타 - 패밀리: BM111-철근콘크리트구조 보; 유형: BM110-철근 콘크리트구조 보_400 x 500_RB4; 유형 ID: 7669455; 패밀리 및 유형: BM111-철근콘크리트구조 보: BM110-철근 콘크리트구조 보_400 x 500_RB4
기하학적 위치 - yz 맞춤: 균일; y 간격띄우기 값: 0 mm; y 맞춤: 원점; z 간격띄우기 값: 0 mm; z 맞춤: 상단; 결합 상태: 두 결합 모두 사용
치수 - 길이: 5500 mm; 단면적: 0.2 m2; 상단 기준 레벨: 43400 mm; 체적: 0.458768 m3; 하단 기준 레벨: 42900 mm

# IfcBeam: BM111-철근콘크리트구조 보:BM110-철근 콘크리트구조 보_400 x 500_RB4, BM111-철근콘크리트구조 보:BM110-철근 콘크리트구조 보_400 x 500_RB4:7669104
In: 옥탑층
Type - ID 데이터 - 유형 마크: B4; 유형 이름: BM110-철근 콘크리트구조 보_400 x 500_RB4
Type - 구조 - 단면 모양: 0
Type - 기타 - 내화구조여부: yes; 주요구조부여부: yes; 카테고리: 구조 프레임; KBIMS-부위코드: E23; 제작정보: bSK-2021_KBIMS2.0-bC; 조달청표준공사코드: AD; 패밀리 이름: BM111-철근콘크리트구조 보
Type - 재료 및 마감재 - 구조 재료: KBIMS-콘크리트
Type - 치수 - 가로치수: 400 mm; 세로치수: 500 mm
Type - Pset_BeamCommon - IsExternal: no; LoadBearing: yes
Material: KBIMS-콘크리트
BaseQuantities - CrossSectionArea: 0.0577561 m2; NetVolume: 0.375414 m3
Pset_BeamCommon - Slope: 0 deg; Reference: BM110-철근 콘크리트구조 보_400 x 500_RB4; Span: 6900 mm
Pset_QuantityTakeOff - Reference: BM110-철근 콘크리트구조 보_400 x 500_RB4; sets with these values: 2
ID 데이터 - 연관 있음: no
공정 - 생성 공정: 새 구성
구속조건 - 끝 레벨 간격띄우기: 0 mm; 단면형상 회전: 0 deg; 방향: 보통; 시작 레벨 간격띄우기: 0 mm; 참조 레벨: 옥탑층; 작업 기준면: 레벨 : 옥탑층; 참조 레벨 입면도: 43400 mm
구조 - 보강 철근 피복 - 다른 면: 보강 철근 피복 1 <25 mm>; 보강 철근 피복 - 하단 면: 보강 철근 피복 1 <25 mm>; 구조적 용도: 기타; 절단 길이: 6500 mm
기타 - 패밀리: BM111-철근콘크리트구조 보; 유형: BM110-철근 콘크리트구조 보_400 x 500_RB4; 유형 ID: 7669455; 패밀리 및 유형: BM111-철근콘크리트구조 보: BM110-철근 콘크리트구조 보_400 x 500_RB4
기하학적 위치 - yz 맞춤: 균일; y 간격띄우기 값: 0 mm; y 맞춤: 원점; z 간격띄우기 값: 0 mm; z 맞춤: 상단; 결합 상태: 두 결합 모두 사용
치수 - 길이: 6900 mm; 단면적: 0.2 m2; 상단 기준 레벨: 43400 mm; 체적: 0.375414 m3; 하단 기준 레벨: 42900 mm

# IfcBeam: BM111-철근콘크리트구조 보:BM110-철근 콘크리트구조 보_400 x 500_RB5 (2)
In: 옥탑층
Type - PredefinedType: BEAM; Material: KBIMS-콘크리트 (2)
Type - ID 데이터 - 유형 마크: B5; 유형 이름: BM110-철근 콘크리트구조 보_400 x 500_RB5
Type - 구조 - 단면 모양: 0
Type - 기타 - 내화구조여부: yes; 주요구조부여부: yes; 카테고리: 구조 프레임; KBIMS-부위코드: E23; 제작정보: bSK-2021_KBIMS2.0-bC; 조달청표준공사코드: AD; 패밀리 이름: BM111-철근콘크리트구조 보
Type - 재료 및 마감재 - 구조 재료: KBIMS-콘크리트
Type - 치수 - 가로치수: 400 mm; 세로치수: 500 mm
Type - Pset_BeamCommon - IsExternal: no; LoadBearing: yes
Pset_BeamCommon - Slope: 0 deg; Reference: BM110-철근 콘크리트구조 보_400 x 500_RB5
Pset_QuantityTakeOff - Reference: BM110-철근 콘크리트구조 보_400 x 500_RB5; sets with these values: 2
ID 데이터 - 연관 있음: no
공정 - 생성 공정: 새 구성
구속조건 - 끝 레벨 간격띄우기: 0 mm; 단면형상 회전: 0 deg; 방향: 보통; 시작 레벨 간격띄우기: 0 mm; 참조 레벨: 옥탑층; 작업 기준면: 레벨 : 옥탑층; 참조 레벨 입면도: 43400 mm
구조 - 보강 철근 피복 - 다른 면: 보강 철근 피복 1 <25 mm>; 보강 철근 피복 - 하단 면: 보강 철근 피복 1 <25 mm>; 구조적 용도: 기타
기타 - 패밀리: BM111-철근콘크리트구조 보; 유형: BM110-철근 콘크리트구조 보_400 x 500_RB5; 유형 ID: 7669454; 패밀리 및 유형: BM111-철근콘크리트구조 보: BM110-철근 콘크리트구조 보_400 x 500_RB5
기하학적 위치 - yz 맞춤: 균일; y 간격띄우기 값: 0 mm; y 맞춤: 원점; z 간격띄우기 값: 0 mm; z 맞춤: 상단; 결합 상태: 두 결합 모두 사용
치수 - 단면적: 0.2 m2; 상단 기준 레벨: 43400 mm; 하단 기준 레벨: 42900 mm
Name (BM111-철근콘크리트구조 보:BM110-철근 콘크리트구조 보_400 x 500_RB5:...) | Span (mm) = 길이 (mm) | CrossSectionArea (m2) | NetVolume (m3) = 체적 (m3) | 절단 길이 (mm)
7669107 | 8047 | 5.2918 | 0.834941 | 7655.98 | BaseQuantities - NetSurfaceArea: 10.5836 m2; 구조 - 보강 철근 피복 - 상단 면: 보강 철근 피복 1 <25 mm>
7669112 | 3050 | 0.05355 | 0.137034 | 2558.99 | Material: KBIMS-콘크리트

# IfcBeam: BM111-철근콘크리트구조 보:BM110-철근 콘크리트구조 보_400 x 500_RG1 (2)
In: 옥탑층
Type - ID 데이터 - 유형 마크: G1; 유형 이름: BM110-철근 콘크리트구조 보_400 x 500_RG1
Type - 구조 - 단면 모양: 0
Type - 기타 - 내화구조여부: yes; 주요구조부여부: yes; 카테고리: 구조 프레임; KBIMS-부위코드: E23; 제작정보: bSK-2021_KBIMS2.0-bC; 조달청표준공사코드: AD; 패밀리 이름: BM111-철근콘크리트구조 보
Type - 재료 및 마감재 - 구조 재료: KBIMS-콘크리트
Type - 치수 - 가로치수: 400 mm; 세로치수: 500 mm
Type - Pset_BeamCommon - IsExternal: no; LoadBearing: yes
Material: KBIMS-콘크리트
Pset_BeamCommon - Slope: 0 deg; Reference: BM110-철근 콘크리트구조 보_400 x 500_RG1
Pset_QuantityTakeOff - Reference: BM110-철근 콘크리트구조 보_400 x 500_RG1; sets with these values: 2
ID 데이터 - 연관 있음: no
공정 - 생성 공정: 새 구성
구속조건 - 끝 레벨 간격띄우기: 0 mm; 단면형상 회전: 0 deg; 방향: 보통; 시작 레벨 간격띄우기: 0 mm; 참조 레벨: 옥탑층; 작업 기준면: 레벨 : 옥탑층; 참조 레벨 입면도: 43400 mm
구조 - 보강 철근 피복 - 다른 면: 보강 철근 피복 1 <25 mm>; 보강 철근 피복 - 하단 면: 보강 철근 피복 1 <25 mm>; 구조적 용도: 기타; 시작 부착 유형: 끝 입면; 끝 부착 유형: 끝 입면; 절단 길이: 9300.01 mm
기타 - 패밀리: BM111-철근콘크리트구조 보; 유형: BM110-철근 콘크리트구조 보_400 x 500_RG1; 유형 ID: 7669439; 패밀리 및 유형: BM111-철근콘크리트구조 보: BM110-철근 콘크리트구조 보_400 x 500_RG1
기하학적 위치 - yz 맞춤: 균일; y 간격띄우기 값: 0 mm; y 맞춤: 원점; z 간격띄우기 값: 0 mm; z 맞춤: 상단; 결합 상태: 두 결합 모두 사용
치수 - 단면적: 0.2 m2; 상단 기준 레벨: 43400 mm; 하단 기준 레벨: 42900 mm
Name (BM111-철근콘크리트구조 보:BM110-철근 콘크리트구조 보_400 x 500_RG1:...) | CrossSectionArea (m2) | NetVolume (m3) = 체적 (m3) | Span (mm) = 길이 (mm)
7669068 | 0.14 | 1.302 | 10050
7669090 | 0.0636999 | 0.59241 | 10100

# IfcBeam: BM111-철근콘크리트구조 보:BM110-철근 콘크리트구조 보_400 x 500_RG2, BM111-철근콘크리트구조 보:BM110-철근 콘크리트구조 보_400 x 500_RG2:7669097
In: 옥탑층
Type - ID 데이터 - 유형 마크: G2; 유형 이름: BM110-철근 콘크리트구조 보_400 x 500_RG2
Type - 구조 - 단면 모양: 0
Type - 기타 - 내화구조여부: yes; 주요구조부여부: yes; 카테고리: 구조 프레임; KBIMS-부위코드: E23; 제작정보: bSK-2021_KBIMS2.0-bC; 조달청표준공사코드: AD; 패밀리 이름: BM111-철근콘크리트구조 보
Type - 재료 및 마감재 - 구조 재료: KBIMS-콘크리트
Type - 치수 - 가로치수: 400 mm; 세로치수: 500 mm
Type - Pset_BeamCommon - IsExternal: no; LoadBearing: yes
Material: KBIMS-콘크리트
BaseQuantities - CrossSectionArea: 0.0637061 m2; NetVolume: 0.445943 m3
Pset_BeamCommon - Slope: 0 deg; Reference: BM110-철근 콘크리트구조 보_400 x 500_RG2; Span: 7000 mm
Pset_QuantityTakeOff - Reference: BM110-철근 콘크리트구조 보_400 x 500_RG2; sets with these values: 2
ID 데이터 - 연관 있음: no
공정 - 생성 공정: 새 구성
구속조건 - 끝 레벨 간격띄우기: 0 mm; 단면형상 회전: 0 deg; 방향: 보통; 시작 레벨 간격띄우기: 0 mm; 참조 레벨: 옥탑층; 작업 기준면: 레벨 : 옥탑층; 참조 레벨 입면도: 43400 mm
구조 - 보강 철근 피복 - 다른 면: 보강 철근 피복 1 <25 mm>; 보강 철근 피복 - 하단 면: 보강 철근 피복 1 <25 mm>; 구조적 용도: 거더; 끝 부착 유형: 끝 입면; 절단 길이: 7000 mm
기타 - 패밀리: BM111-철근콘크리트구조 보; 유형: BM110-철근 콘크리트구조 보_400 x 500_RG2; 유형 ID: 7669453; 패밀리 및 유형: BM111-철근콘크리트구조 보: BM110-철근 콘크리트구조 보_400 x 500_RG2
기하학적 위치 - yz 맞춤: 균일; y 간격띄우기 값: 0 mm; y 맞춤: 원점; z 간격띄우기 값: 0 mm; z 맞춤: 상단; 결합 상태: 두 결합 모두 사용
치수 - 길이: 7000 mm; 단면적: 0.2 m2; 상단 기준 레벨: 43400 mm; 체적: 0.445943 m3; 하단 기준 레벨: 42900 mm

# IfcBeam: BM111-철근콘크리트구조 보:BM110-철근 콘크리트구조 보_400 x 500_RG3 (2)
In: 옥탑층
Type - ID 데이터 - 유형 마크: G3; 유형 이름: BM110-철근 콘크리트구조 보_400 x 500_RG3
Type - 구조 - 단면 모양: 0
Type - 기타 - 내화구조여부: yes; 주요구조부여부: yes; 카테고리: 구조 프레임; KBIMS-부위코드: E23; 제작정보: bSK-2021_KBIMS2.0-bC; 조달청표준공사코드: AD; 패밀리 이름: BM111-철근콘크리트구조 보
Type - 재료 및 마감재 - 구조 재료: KBIMS-콘크리트
Type - 치수 - 가로치수: 400 mm; 세로치수: 500 mm
Type - Pset_BeamCommon - IsExternal: no; LoadBearing: yes
Material: KBIMS-콘크리트
BaseQuantities - CrossSectionArea: 0.14 m2
Pset_BeamCommon - Slope: 0 deg; Reference: BM110-철근 콘크리트구조 보_400 x 500_RG3
Pset_QuantityTakeOff - Reference: BM110-철근 콘크리트구조 보_400 x 500_RG3; sets with these values: 2
ID 데이터 - 연관 있음: no
공정 - 생성 공정: 새 구성
구속조건 - 끝 레벨 간격띄우기: 0 mm; 단면형상 회전: 0 deg; 방향: 보통; 시작 레벨 간격띄우기: 0 mm; 참조 레벨: 옥탑층; 작업 기준면: 레벨 : 옥탑층; 참조 레벨 입면도: 43400 mm
구조 - 보강 철근 피복 - 다른 면: 보강 철근 피복 1 <25 mm>; 보강 철근 피복 - 하단 면: 보강 철근 피복 1 <25 mm>; 구조적 용도: 기타; 시작 부착 유형: 끝 입면
기타 - 패밀리: BM111-철근콘크리트구조 보; 유형: BM110-철근 콘크리트구조 보_400 x 500_RG3; 유형 ID: 7669452; 패밀리 및 유형: BM111-철근콘크리트구조 보: BM110-철근 콘크리트구조 보_400 x 500_RG3
기하학적 위치 - yz 맞춤: 균일; y 간격띄우기 값: 0 mm; y 맞춤: 원점; z 간격띄우기 값: 0 mm; z 맞춤: 상단; 결합 상태: 두 결합 모두 사용
치수 - 단면적: 0.2 m2; 상단 기준 레벨: 43400 mm; 하단 기준 레벨: 42900 mm
Name (BM111-철근콘크리트구조 보:BM110-철근 콘크리트구조 보_400 x 500_RG3:...) | NetVolume (m3) = 체적 (m3) | Span (mm) = 길이 (mm) | 절단 길이 (mm)
7669067 | 0.347481 | 2850 | 2482.01
7669096 | 0.321999 | 2750 | 2299.99

# IfcBeam: BM111-철근콘크리트구조 보:BM110-철근 콘크리트구조 보_400 x 500_RG4 (2)
In: 옥탑층
Type - ID 데이터 - 유형 마크: G4; 유형 이름: BM110-철근 콘크리트구조 보_400 x 500_RG4
Type - 구조 - 단면 모양: 0
Type - 기타 - 내화구조여부: yes; 주요구조부여부: yes; 카테고리: 구조 프레임; KBIMS-부위코드: E23; 제작정보: bSK-2021_KBIMS2.0-bC; 조달청표준공사코드: AD; 패밀리 이름: BM111-철근콘크리트구조 보
Type - 재료 및 마감재 - 구조 재료: KBIMS-콘크리트
Type - 치수 - 가로치수: 400 mm; 세로치수: 500 mm
Type - Pset_BeamCommon - IsExternal: no; LoadBearing: yes
Material: KBIMS-콘크리트
Pset_BeamCommon - Slope: 0 deg; Reference: BM110-철근 콘크리트구조 보_400 x 500_RG4
Pset_QuantityTakeOff - Reference: BM110-철근 콘크리트구조 보_400 x 500_RG4; sets with these values: 2
ID 데이터 - 연관 있음: no
공정 - 생성 공정: 새 구성
구속조건 - 끝 레벨 간격띄우기: 0 mm; 단면형상 회전: 0 deg; 방향: 보통; 시작 레벨 간격띄우기: 0 mm; 참조 레벨: 옥탑층; 작업 기준면: 레벨 : 옥탑층; 참조 레벨 입면도: 43400 mm
구조 - 보강 철근 피복 - 다른 면: 보강 철근 피복 1 <25 mm>; 보강 철근 피복 - 하단 면: 보강 철근 피복 1 <25 mm>; 시작 부착 유형: 끝 입면; 구조적 용도: 거더; 끝 부착 유형: 끝 입면; 절단 길이: 6500 mm
기타 - 패밀리: BM111-철근콘크리트구조 보; 유형: BM110-철근 콘크리트구조 보_400 x 500_RG4; 유형 ID: 7669442; 패밀리 및 유형: BM111-철근콘크리트구조 보: BM110-철근 콘크리트구조 보_400 x 500_RG4
기하학적 위치 - yz 맞춤: 균일; y 간격띄우기 값: 0 mm; y 맞춤: 원점; z 간격띄우기 값: 0 mm; z 맞춤: 상단; 결합 상태: 두 결합 모두 사용
치수 - 단면적: 0.2 m2; 상단 기준 레벨: 43400 mm; 하단 기준 레벨: 42900 mm
Name (BM111-철근콘크리트구조 보:BM110-철근 콘크리트구조 보_400 x 500_RG4:...) | CrossSectionArea (m2) | NetVolume (m3) = 체적 (m3) | Span (mm) = 길이 (mm)
7669080 | 4.13133 | 0.600717 | 7250
7669081 | 0.14 | 0.91 | 6950

# IfcBeam: BM111-철근콘크리트구조 보:BM110-철근 콘크리트구조 보_400 x 500_RG6 (3)
In: 옥탑층
Type - ID 데이터 - 유형 마크: G6; 유형 이름: BM110-철근 콘크리트구조 보_400 x 500_RG6
Type - 구조 - 단면 모양: 0
Type - 기타 - 내화구조여부: yes; 주요구조부여부: yes; 카테고리: 구조 프레임; KBIMS-부위코드: E23; 제작정보: bSK-2021_KBIMS2.0-bC; 조달청표준공사코드: AD; 패밀리 이름: BM111-철근콘크리트구조 보
Type - 재료 및 마감재 - 구조 재료: KBIMS-콘크리트
Type - 치수 - 가로치수: 400 mm; 세로치수: 500 mm
Type - Pset_BeamCommon - IsExternal: no; LoadBearing: yes
Material: KBIMS-콘크리트
BaseQuantities - CrossSectionArea: 0.14 m2; NetVolume: 1.554 m3
Pset_BeamCommon - Slope: 0 deg; Reference: BM110-철근 콘크리트구조 보_400 x 500_RG6
Pset_QuantityTakeOff - Reference: BM110-철근 콘크리트구조 보_400 x 500_RG6; sets with these values: 2
ID 데이터 - 연관 있음: no
공정 - 생성 공정: 새 구성
구속조건 - 끝 레벨 간격띄우기: 0 mm; 단면형상 회전: 0 deg; 방향: 보통; 시작 레벨 간격띄우기: 0 mm; 참조 레벨: 옥탑층; 작업 기준면: 레벨 : 옥탑층; 참조 레벨 입면도: 43400 mm
구조 - 보강 철근 피복 - 다른 면: 보강 철근 피복 1 <25 mm>; 보강 철근 피복 - 하단 면: 보강 철근 피복 1 <25 mm>; 시작 부착 유형: 끝 입면; 구조적 용도: 거더; 끝 부착 유형: 끝 입면; 절단 길이: 11100 mm
기타 - 패밀리: BM111-철근콘크리트구조 보; 유형: BM110-철근 콘크리트구조 보_400 x 500_RG6; 유형 ID: 7669444; 패밀리 및 유형: BM111-철근콘크리트구조 보: BM110-철근 콘크리트구조 보_400 x 500_RG6
기하학적 위치 - yz 맞춤: 균일; y 간격띄우기 값: 0 mm; y 맞춤: 원점; z 간격띄우기 값: 0 mm; z 맞춤: 상단; 결합 상태: 두 결합 모두 사용
치수 - 단면적: 0.2 m2; 상단 기준 레벨: 43400 mm; 체적: 1.554 m3; 하단 기준 레벨: 42900 mm
Name (BM111-철근콘크리트구조 보:BM110-철근 콘크리트구조 보_400 x 500_RG6:...) | Span (mm) = 길이 (mm)
7669071 | 11850
7669074 | 11800
7669077 | 12000

# IfcBeam: BM111-철근콘크리트구조 보:BM110-철근 콘크리트구조 보_400 x 500_RG7 (5)
In: 옥탑층
Type - ID 데이터 - 유형 마크: G7; 유형 이름: BM110-철근 콘크리트구조 보_400 x 500_RG7
Type - 구조 - 단면 모양: 0
Type - 기타 - 내화구조여부: yes; 주요구조부여부: yes; 카테고리: 구조 프레임; KBIMS-부위코드: E23; 제작정보: bSK-2021_KBIMS2.0-bC; 조달청표준공사코드: AD; 패밀리 이름: BM111-철근콘크리트구조 보
Type - 재료 및 마감재 - 구조 재료: KBIMS-콘크리트
Type - 치수 - 가로치수: 400 mm; 세로치수: 500 mm
Type - Pset_BeamCommon - IsExternal: no; LoadBearing: yes
Material: KBIMS-콘크리트
Pset_BeamCommon - Slope: 0 deg; Reference: BM110-철근 콘크리트구조 보_400 x 500_RG7
Pset_QuantityTakeOff - Reference: BM110-철근 콘크리트구조 보_400 x 500_RG7; sets with these values: 2
ID 데이터 - 연관 있음: no
공정 - 생성 공정: 새 구성
구속조건 - 끝 레벨 간격띄우기: 0 mm; 단면형상 회전: 0 deg; 방향: 보통; 시작 레벨 간격띄우기: 0 mm; 작업 기준면: 레벨 : 옥탑층; 참조 레벨: 옥탑층; 참조 레벨 입면도: 43400 mm
구조 - 보강 철근 피복 - 다른 면: 보강 철근 피복 1 <25 mm>; 보강 철근 피복 - 하단 면: 보강 철근 피복 1 <25 mm>; 시작 부착 유형: 끝 입면; 끝 부착 유형: 끝 입면; 절단 길이: 12100 mm
기타 - 패밀리: BM111-철근콘크리트구조 보; 유형: BM110-철근 콘크리트구조 보_400 x 500_RG7; 유형 ID: 7669446; 패밀리 및 유형: BM111-철근콘크리트구조 보: BM110-철근 콘크리트구조 보_400 x 500_RG7
기하학적 위치 - yz 맞춤: 균일; y 간격띄우기 값: 0 mm; y 맞춤: 원점; z 간격띄우기 값: 0 mm; z 맞춤: 상단; 결합 상태: 두 결합 모두 사용
치수 - 단면적: 0.2 m2; 상단 기준 레벨: 43400 mm; 하단 기준 레벨: 42900 mm
Name (BM111-철근콘크리트구조 보:BM110-철근 콘크리트구조 보_400 x 500_RG7:...) | CrossSectionArea (m2) | NetVolume (m3) = 체적 (m3) | Span (mm) = 길이 (mm) | 구조적 용도
7669057 | 0.14 | 1.694 | 12900 | 기타
7669062 | 0.14 | 1.694 | 13000 | 기타
7669066 | 0.14 | 1.694 | 12800 | 기타
7669095 | 0.14 | 1.694 | 13000 | 기타
7669098 | 0.0636999 | 0.770769 | 12650 | 거더

# IfcBeam: BM111-철근콘크리트구조 보:BM110-철근 콘크리트구조 보_400 x 500_RG8 (3)
In: 옥탑층
Type - ID 데이터 - 유형 마크: G8; 유형 이름: BM110-철근 콘크리트구조 보_400 x 500_RG8
Type - 구조 - 단면 모양: 0
Type - 기타 - 내화구조여부: yes; 주요구조부여부: yes; 카테고리: 구조 프레임; KBIMS-부위코드: E23; 제작정보: bSK-2021_KBIMS2.0-bC; 조달청표준공사코드: AD; 패밀리 이름: BM111-철근콘크리트구조 보
Type - 재료 및 마감재 - 구조 재료: KBIMS-콘크리트
Type - 치수 - 가로치수: 400 mm; 세로치수: 500 mm
Type - Pset_BeamCommon - IsExternal: no; LoadBearing: yes
Material: KBIMS-콘크리트
Pset_BeamCommon - Slope: 0 deg; Reference: BM110-철근 콘크리트구조 보_400 x 500_RG8
Pset_QuantityTakeOff - Reference: BM110-철근 콘크리트구조 보_400 x 500_RG8; sets with these values: 2
ID 데이터 - 연관 있음: no
공정 - 생성 공정: 새 구성
구속조건 - 끝 레벨 간격띄우기: 0 mm; 단면형상 회전: 0 deg; 방향: 보통; 시작 레벨 간격띄우기: 0 mm; 참조 레벨: 옥탑층; 작업 기준면: 레벨 : 옥탑층; 참조 레벨 입면도: 43400 mm
구조 - 보강 철근 피복 - 다른 면: 보강 철근 피복 1 <25 mm>; 보강 철근 피복 - 하단 면: 보강 철근 피복 1 <25 mm>; 시작 부착 유형: 끝 입면; 끝 부착 유형: 끝 입면
기타 - 패밀리: BM111-철근콘크리트구조 보; 유형: BM110-철근 콘크리트구조 보_400 x 500_RG8; 유형 ID: 7669449; 패밀리 및 유형: BM111-철근콘크리트구조 보: BM110-철근 콘크리트구조 보_400 x 500_RG8
기하학적 위치 - yz 맞춤: 균일; y 간격띄우기 값: 0 mm; y 맞춤: 원점; z 간격띄우기 값: 0 mm; z 맞춤: 상단; 결합 상태: 두 결합 모두 사용
치수 - 단면적: 0.2 m2; 상단 기준 레벨: 43400 mm; 하단 기준 레벨: 42900 mm
Name (BM111-철근콘크리트구조 보:BM110-철근 콘크리트구조 보_400 x 500_RG8:...) | CrossSectionArea (m2) | NetVolume (m3) = 체적 (m3) | Span (mm) = 길이 (mm) | 구조적 용도 | 절단 길이 (mm)
7669058 | 0.14 | 0.35 | 3000 | 기타 | 2500
7669063 | 0.14 | 0.35 | 3300 | 기타 | 2500
7669099 | 0.0636999 | 0.133769 | 2549 | 거더 | 2099.98

# IfcBeam: BM111-철근콘크리트구조 보:BM110-철근 콘크리트구조 보_400 x 500_RWG1 (10)
In: 옥탑층
Type - PredefinedType: BEAM; Material: KBIMS-콘크리트
Type - ID 데이터 - 유형 마크: WG1; 유형 이름: BM110-철근 콘크리트구조 보_400 x 500_RWG1
Type - 구조 - 단면 모양: 0
Type - 기타 - 내화구조여부: yes; 주요구조부여부: yes; 카테고리: 구조 프레임; KBIMS-부위코드: E23; 제작정보: bSK-2021_KBIMS2.0-bC; 조달청표준공사코드: AD; 패밀리 이름: BM111-철근콘크리트구조 보
Type - 재료 및 마감재 - 구조 재료: KBIMS-콘크리트
Type - 치수 - 가로치수: 400 mm; 세로치수: 500 mm
Type - Pset_BeamCommon - IsExternal: no; LoadBearing: yes
Pset_BeamCommon - Slope: 0 deg; Reference: BM110-철근 콘크리트구조 보_400 x 500_RWG1
Pset_QuantityTakeOff - Reference: BM110-철근 콘크리트구조 보_400 x 500_RWG1; sets with these values: 2
ID 데이터 - 연관 있음: no
공정 - 생성 공정: 새 구성
구속조건 - 끝 레벨 간격띄우기: 0 mm; 단면형상 회전: 0 deg; 방향: 보통; 시작 레벨 간격띄우기: 0 mm
구조 - 보강 철근 피복 - 다른 면: 보강 철근 피복 1 <25 mm>; 보강 철근 피복 - 하단 면: 보강 철근 피복 1 <25 mm>
기타 - 패밀리: BM111-철근콘크리트구조 보; 유형: BM110-철근 콘크리트구조 보_400 x 500_RWG1; 유형 ID: 7669415; 패밀리 및 유형: BM111-철근콘크리트구조 보: BM110-철근 콘크리트구조 보_400 x 500_RWG1
기하학적 위치 - yz 맞춤: 균일; y 간격띄우기 값: 0 mm; y 맞춤: 원점; z 간격띄우기 값: 0 mm; z 맞춤: 상단; 결합 상태: 두 결합 모두 사용
치수 - 단면적: 0.2 m2
Name (BM111-철근콘크리트구조 보:BM110-철근 콘크리트구조 보_400 x 500_RWG1:...) | Span (mm) = 길이 (mm) | CrossSectionArea (m2) | NetVolume (m3) = 체적 (m3) | 작업 기준면 | 참조 레벨 | 참조 레벨 입면도 (mm) = 상단 기준 레벨 (mm) | 구조적 용도 | 절단 길이 (mm) | 하단 기준 레벨 (mm)
7669049 | 6704 | 0.0700061 | 0.441546 | 레벨 : 지붕층 | 지붕층 | 47400 | 거더 | 6703.91 | 46900 | BaseQuantities - Length: 5503.91 mm; OuterSurfaceArea: 6.05449 m2; GrossSurfaceArea: 6.1945 m2; GrossVolume: 0.385307 m3; NetSurfaceArea: 7.33884 m2; 구조 - 보강 철근 피복 - 상단 면: 보강 철근 피복 1 <25 mm>
7669050 | 10702 | 0.0700001 | 0.685286 | 레벨 : 지붕층 | 지붕층 | 47400 | 기타 | 10501.8 | 46900 | BaseQuantities - Length: 1999.99 mm; OuterSurfaceArea: 2.19999 m2; GrossSurfaceArea: 2.33999 m2; GrossVolume: 0.14 m3; NetSurfaceArea: 14.4658 m2; 구조 - 보강 철근 피복 - 상단 면: 보강 철근 피복 1 <25 mm>
7669051 | 4404 | 0.0699939 | 0.266251 | 레벨 : 지붕층 | 지붕층 | 47400 | 기타 | 4003.91 | 46900 | BaseQuantities - Length: 1500 mm; OuterSurfaceArea: 1.64995 m2; GrossSurfaceArea: 1.78994 m2; GrossVolume: 0.104991 m3; NetSurfaceArea: 4.46414 m2
7669052 | 8000 | 0.0699939 | 0.531954 | 레벨 : 지붕층 | 지붕층 | 47400 | 기타 | 7800 | 46900 | BaseQuantities - Length: 5500 mm; OuterSurfaceArea: 6.04981 m2; GrossSurfaceArea: 6.1898 m2; GrossVolume: 0.384967 m3; NetSurfaceArea: 8.63971 m2
7669054 | 10602 | 0.0699999 | 0.665128 | 레벨 : 지붕층 | 지붕층 | 47400 | 기타 | 10101.8 | 46900 | BaseQuantities - Length: 1999.99 mm; OuterSurfaceArea: 2.19999 m2; GrossSurfaceArea: 2.33999 m2; GrossVolume: 0.139999 m3; NetSurfaceArea: 11.012 m2
7669100 | 10900 | 6.83165 | 0.926089 | 레벨 : 옥탑층 | 옥탑층 | 43400 | 기타 | 10900 | 42900
7669101 | 4400 | 0.0637061 | 0.254824 | 레벨 : 옥탑층 | 옥탑층 | 43400 | 기타 | 4000 | 42900
7669102 | 8200 | 0.0637061 | 0.509648 | 레벨 : 옥탑층 | 옥탑층 | 43400 | 기타 | 8000 | 42900
7669113 | 2802 | 0.0699999 | 0.16813 | 레벨 : 지붕층 | 지붕층 | 47400 | 기타 | 2401.86 | 46900
7669114 | 5800 | 0.070003 | 0.371016 | 레벨 : 지붕층 | 지붕층 | 47400 | 기타 | 5300 | 46900

# IfcBeam: BM111-철근콘크리트구조 보:BM110-철근 콘크리트구조 보_400 x 500_RWG1, BM111-철근콘크리트구조 보:BM110-철근 콘크리트구조 보_400 x 500_RWG1:7669053
In: 옥탑층
Type - PredefinedType: BEAM; Material: KBIMS-콘크리트 (4)
Type - ID 데이터 - 유형 마크: WG1; 유형 이름: BM110-철근 콘크리트구조 보_400 x 500_RWG1
Type - 구조 - 단면 모양: 0
Type - 기타 - 내화구조여부: yes; 주요구조부여부: yes; 카테고리: 구조 프레임; KBIMS-부위코드: E23; 제작정보: bSK-2021_KBIMS2.0-bC; 조달청표준공사코드: AD; 패밀리 이름: BM111-철근콘크리트구조 보
Type - 재료 및 마감재 - 구조 재료: KBIMS-콘크리트
Type - 치수 - 가로치수: 400 mm; 세로치수: 500 mm
Type - Pset_BeamCommon - IsExternal: no; LoadBearing: yes
Pset_BeamCommon - Slope: 0 deg; Reference: BM110-철근 콘크리트구조 보_400 x 500_RWG1; Span: 6504 mm
Pset_QuantityTakeOff - Reference: BM110-철근 콘크리트구조 보_400 x 500_RWG1; sets with these values: 2
BaseQuantities - Length: 2803.91 mm; CrossSectionArea: 0.0349969 m2; OuterSurfaceArea: 2.52347 m2; GrossSurfaceArea: 2.59346 m2; GrossVolume: 0.0981281 m3; NetVolume: 0.602274 m3; NetSurfaceArea: 10.097 m2
ID 데이터 - 연관 있음: no
공정 - 생성 공정: 새 구성
구속조건 - 끝 레벨 간격띄우기: 0 mm; 단면형상 회전: 0 deg; 방향: 보통; 시작 레벨 간격띄우기: 0 mm; 참조 레벨: 지붕층; 작업 기준면: 레벨 : 지붕층; 참조 레벨 입면도: 47400 mm
구조 - 보강 철근 피복 - 다른 면: 보강 철근 피복 1 <25 mm>; 보강 철근 피복 - 하단 면: 보강 철근 피복 1 <25 mm>; 구조적 용도: 기타; 절단 길이: 6103.91 mm
기타 - 패밀리: BM111-철근콘크리트구조 보; 유형: BM110-철근 콘크리트구조 보_400 x 500_RWG1; 유형 ID: 7669415; 패밀리 및 유형: BM111-철근콘크리트구조 보: BM110-철근 콘크리트구조 보_400 x 500_RWG1
기하학적 위치 - yz 맞춤: 균일; y 간격띄우기 값: 0 mm; y 맞춤: 원점; z 간격띄우기 값: 0 mm; z 맞춤: 상단; 결합 상태: 두 결합 모두 사용
치수 - 길이: 6504 mm; 단면적: 0.2 m2; 상단 기준 레벨: 47400 mm; 체적: 0.602274 m3; 하단 기준 레벨: 46900 mm

# IfcBeam: BM111-철근콘크리트구조 보:BM110-철근 콘크리트구조 보_400 x 500_RWG2, BM111-철근콘크리트구조 보:BM110-철근 콘크리트구조 보_400 x 500_RWG2:7669105
In: 옥탑층
Type - PredefinedType: BEAM; Material: KBIMS-콘크리트
Type - ID 데이터 - 유형 마크: WG2; 유형 이름: BM110-철근 콘크리트구조 보_400 x 500_RWG2
Type - 구조 - 단면 모양: 0
Type - 기타 - 내화구조여부: yes; 주요구조부여부: yes; 카테고리: 구조 프레임; KBIMS-부위코드: E23; 제작정보: bSK-2021_KBIMS2.0-bC; 조달청표준공사코드: AD; 패밀리 이름: BM111-철근콘크리트구조 보
Type - 재료 및 마감재 - 구조 재료: KBIMS-콘크리트
Type - 치수 - 가로치수: 400 mm; 세로치수: 500 mm
Type - Pset_BeamCommon - IsExternal: no; LoadBearing: yes
Pset_BeamCommon - Slope: 0 deg; Reference: BM110-철근 콘크리트구조 보_400 x 500_RWG2; Span: 7988 mm
Pset_QuantityTakeOff - Reference: BM110-철근 콘크리트구조 보_400 x 500_RWG2; sets with these values: 2
BaseQuantities - Length: 2561.01 mm; CrossSectionArea: 0.0909999 m2; OuterSurfaceArea: 3.49321 m2; GrossSurfaceArea: 3.67521 m2; GrossVolume: 0.233052 m3; NetVolume: 0.602998 m3; NetSurfaceArea: 9.65589 m2
ID 데이터 - 연관 있음: no
공정 - 생성 공정: 새 구성
구속조건 - 끝 레벨 간격띄우기: 0 mm; 단면형상 회전: 0 deg; 방향: 보통; 시작 레벨 간격띄우기: 0 mm; 참조 레벨: 옥탑층; 작업 기준면: 레벨 : 옥탑층; 참조 레벨 입면도: 43400 mm
구조 - 보강 철근 피복 - 다른 면: 보강 철근 피복 1 <25 mm>; 보강 철근 피복 - 상단 면: 보강 철근 피복 1 <25 mm>; 보강 철근 피복 - 하단 면: 보강 철근 피복 1 <25 mm>; 구조적 용도: 기타; 절단 길이: 7481.98 mm
기타 - 패밀리: BM111-철근콘크리트구조 보; 유형: BM110-철근 콘크리트구조 보_400 x 500_RWG2; 유형 ID: 7669416; 패밀리 및 유형: BM111-철근콘크리트구조 보: BM110-철근 콘크리트구조 보_400 x 500_RWG2
기하학적 위치 - yz 맞춤: 균일; y 간격띄우기 값: 0 mm; y 맞춤: 원점; z 간격띄우기 값: 0 mm; z 맞춤: 상단; 결합 상태: 두 결합 모두 사용
치수 - 길이: 7988 mm; 단면적: 0.2 m2; 상단 기준 레벨: 43400 mm; 체적: 0.602998 m3; 하단 기준 레벨: 42900 mm

# IfcBeam: BM111-철근콘크리트구조 보:BM110-철근 콘크리트구조 보_400 x 500_RWG2, BM111-철근콘크리트구조 보:BM110-철근 콘크리트구조 보_400 x 500_RWG2:7669103
In: 옥탑층
Type - ID 데이터 - 유형 마크: WG2; 유형 이름: BM110-철근 콘크리트구조 보_400 x 500_RWG2
Type - 구조 - 단면 모양: 0
Type - 기타 - 내화구조여부: yes; 주요구조부여부: yes; 카테고리: 구조 프레임; KBIMS-부위코드: E23; 제작정보: bSK-2021_KBIMS2.0-bC; 조달청표준공사코드: AD; 패밀리 이름: BM111-철근콘크리트구조 보
Type - 재료 및 마감재 - 구조 재료: KBIMS-콘크리트
Type - 치수 - 가로치수: 400 mm; 세로치수: 500 mm
Type - Pset_BeamCommon - IsExternal: no; LoadBearing: yes
Material: KBIMS-콘크리트
BaseQuantities - CrossSectionArea: 0.0696409 m2; NetVolume: 0.451412 m3
Pset_BeamCommon - Slope: 0 deg; Reference: BM110-철근 콘크리트구조 보_400 x 500_RWG2; Span: 6900 mm
Pset_QuantityTakeOff - Reference: BM110-철근 콘크리트구조 보_400 x 500_RWG2; sets with these values: 2
ID 데이터 - 연관 있음: no
공정 - 생성 공정: 새 구성
구속조건 - 끝 레벨 간격띄우기: 0 mm; 단면형상 회전: 0 deg; 방향: 보통; 시작 레벨 간격띄우기: 0 mm; 참조 레벨: 옥탑층; 작업 기준면: 레벨 : 옥탑층; 참조 레벨 입면도: 43400 mm
구조 - 보강 철근 피복 - 다른 면: 보강 철근 피복 1 <25 mm>; 보강 철근 피복 - 하단 면: 보강 철근 피복 1 <25 mm>; 구조적 용도: 기타; 절단 길이: 6482 mm
기타 - 패밀리: BM111-철근콘크리트구조 보; 유형: BM110-철근 콘크리트구조 보_400 x 500_RWG2; 유형 ID: 7669416; 패밀리 및 유형: BM111-철근콘크리트구조 보: BM110-철근 콘크리트구조 보_400 x 500_RWG2
기하학적 위치 - yz 맞춤: 균일; y 간격띄우기 값: 0 mm; y 맞춤: 원점; z 간격띄우기 값: 0 mm; z 맞춤: 상단; 결합 상태: 두 결합 모두 사용
치수 - 길이: 6900 mm; 단면적: 0.2 m2; 상단 기준 레벨: 43400 mm; 체적: 0.451412 m3; 하단 기준 레벨: 42900 mm

# IfcBeam: BM111-철근콘크리트구조 보:BM110-철근 콘크리트구조 보_400 x 600_1B3 (3)
In: 지상 1층
Type - PredefinedType: BEAM; Material: KBIMS-콘크리트
Type - ID 데이터 - 유형 마크: B3; 유형 이름: BM110-철근 콘크리트구조 보_400 x 600_1B3
Type - 구조 - 단면 모양: 0
Type - 기타 - 내화구조여부: yes; 주요구조부여부: yes; 카테고리: 구조 프레임; KBIMS-부위코드: E23; 제작정보: bSK-2021_KBIMS2.0-bC; 조달청표준공사코드: AD; 패밀리 이름: BM111-철근콘크리트구조 보
Type - 재료 및 마감재 - 구조 재료: KBIMS-콘크리트
Type - 치수 - 가로치수: 400 mm; 세로치수: 600 mm
Type - Pset_BeamCommon - IsExternal: no; LoadBearing: yes
Pset_BeamCommon - Slope: 0 deg; Reference: BM110-철근 콘크리트구조 보_400 x 600_1B3
Pset_QuantityTakeOff - Reference: BM110-철근 콘크리트구조 보_400 x 600_1B3; sets with these values: 2
ID 데이터 - 연관 있음: no
공정 - 생성 공정: 새 구성
구속조건 - 단면형상 회전: 0 deg; 참조 레벨: 지상 1층; 참조 레벨 입면도: 0 mm
구조 - 보강 철근 피복 - 다른 면: 보강 철근 피복 1 <25 mm>; 보강 철근 피복 - 하단 면: 보강 철근 피복 1 <25 mm>; 구조적 용도: 거더
기타 - 패밀리: BM111-철근콘크리트구조 보; 유형: BM110-철근 콘크리트구조 보_400 x 600_1B3; 유형 ID: 7667216; 패밀리 및 유형: BM111-철근콘크리트구조 보: BM110-철근 콘크리트구조 보_400 x 600_1B3
기하학적 위치 - yz 맞춤: 균일; y 간격띄우기 값: 0 mm; y 맞춤: 원점; z 맞춤: 상단; 결합 상태: 두 결합 모두 사용
치수 - 단면적: 0.24 m2
Name (BM111-철근콘크리트구조 보:BM110-철근 콘크리트구조 보_400 x 600_1B3:...) | Span (mm) = 길이 (mm) | Length (mm) | CrossSectionArea (m2) | OuterSurfaceArea (m2) | GrossSurfaceArea (m2) | GrossVolume (m3) | NetVolume (m3) = 체적 (m3) | NetSurfaceArea (m2) | 끝 레벨 간격띄우기 (mm) = 시작 레벨 간격띄우기 (mm) | 보강 철근 피복 - 상단 면 | 절단 길이 (mm) | z 간격띄우기 값 (mm) | 상단 기준 레벨 (mm) | 하단 기준 레벨 (mm)
7667177 | 7336 | 86.1352 | 0.24 | 0.17227 | 0.65227 | 0.0206724 | 0.978454 | 10.5501 | -550 | 보강 철근 피복 1 <25 mm> | 6786.14 | 0 | -550 | -1150
7668321 | 7450 | 86.1352 | 0.0451797 | 0.116334 | 0.206693 | 0.00389156 | 0.184193 | 5.95735 | -550 | 보강 철근 피복 1 <25 mm> | 6786.14 | 0 | -550 | -1150
7668325 | 6450 |  | 5.19 |  |  |  | 1.004 |  | 0 |  | 6300 | -2100 | -2100 | -2700 | 구속조건 - 방향: 보통; 작업 기준면: 레벨 : 지상 1층

# IfcBeam: BM111-철근콘크리트구조 보:BM110-철근 콘크리트구조 보_400 x 600_B1B4 (2)
In: 지하1층
Type - ID 데이터 - 유형 마크: B4; 유형 이름: BM110-철근 콘크리트구조 보_400 x 600_B1B4
Type - 구조 - 단면 모양: 0
Type - 기타 - 내화구조여부: yes; 주요구조부여부: yes; 카테고리: 구조 프레임; KBIMS-부위코드: E23; 제작정보: bSK-2021_KBIMS2.0-bC; 조달청표준공사코드: AD; 패밀리 이름: BM111-철근콘크리트구조 보
Type - 재료 및 마감재 - 구조 재료: KBIMS-콘크리트
Type - 치수 - 가로치수: 400 mm; 세로치수: 600 mm
Type - Pset_BeamCommon - IsExternal: no; LoadBearing: yes
Material: KBIMS-콘크리트
Pset_BeamCommon - Slope: 0 deg; Reference: BM110-철근 콘크리트구조 보_400 x 600_B1B4
Pset_QuantityTakeOff - Reference: BM110-철근 콘크리트구조 보_400 x 600_B1B4; sets with these values: 2
ID 데이터 - 연관 있음: no
공정 - 생성 공정: 새 구성
구속조건 - 끝 레벨 간격띄우기: 0 mm; 단면형상 회전: 0 deg; 방향: 보통; 시작 레벨 간격띄우기: 0 mm; 참조 레벨: 지하1층; 작업 기준면: 레벨 : 지하1층; 참조 레벨 입면도: -6100 mm
구조 - 보강 철근 피복 - 다른 면: 보강 철근 피복 1 <25 mm>; 보강 철근 피복 - 하단 면: 보강 철근 피복 1 <25 mm>
기타 - 패밀리: BM111-철근콘크리트구조 보; 유형: BM110-철근 콘크리트구조 보_400 x 600_B1B4; 유형 ID: 7669402; 패밀리 및 유형: BM111-철근콘크리트구조 보: BM110-철근 콘크리트구조 보_400 x 600_B1B4
기하학적 위치 - yz 맞춤: 균일; y 간격띄우기 값: 0 mm; y 맞춤: 원점; z 간격띄우기 값: 0 mm; z 맞춤: 상단; 결합 상태: 두 결합 모두 사용
치수 - 단면적: 0.24 m2; 상단 기준 레벨: -6100 mm; 하단 기준 레벨: -6700 mm
Name (BM111-철근콘크리트구조 보:BM110-철근 콘크리트구조 보_400 x 600_B1B4:...) | CrossSectionArea (m2) | NetVolume (m3) = 체적 (m3) | Span (mm) = 길이 (mm) | 구조적 용도 | 절단 길이 (mm)
7668218 | 0.16 | 0.783998 | 5250 | 기타 | 4899.99
7668225 | 0.0800069 | 0.232141 | 3352 | 거더 | 2901.51

# IfcBeam: BM111-철근콘크리트구조 보:BM110-철근 콘크리트구조 보_400 x 800_1B5 (4)
In: 지상 1층
Type - PredefinedType: BEAM; Material: KBIMS-콘크리트 (2)
Type - ID 데이터 - 유형 마크: B5; 유형 이름: BM110-철근 콘크리트구조 보_400 x 800_1B5
Type - 구조 - 단면 모양: 0
Type - 기타 - 내화구조여부: yes; 주요구조부여부: yes; 카테고리: 구조 프레임; KBIMS-부위코드: E23; 제작정보: bSK-2021_KBIMS2.0-bC; 조달청표준공사코드: AD; 패밀리 이름: BM111-철근콘크리트구조 보
Type - 재료 및 마감재 - 구조 재료: KBIMS-콘크리트
Type - 치수 - 가로치수: 400 mm; 세로치수: 800 mm
Type - Pset_BeamCommon - IsExternal: no; LoadBearing: yes
Pset_BeamCommon - Slope: 0 deg; Reference: BM110-철근 콘크리트구조 보_400 x 800_1B5
Pset_QuantityTakeOff - Reference: BM110-철근 콘크리트구조 보_400 x 800_1B5; sets with these values: 2
ID 데이터 - 연관 있음: no
공정 - 생성 공정: 새 구성
구속조건 - 끝 레벨 간격띄우기: 0 mm; 단면형상 회전: 0 deg; 방향: 보통; 시작 레벨 간격띄우기: 0 mm; 참조 레벨: 지상 1층; 참조 레벨 입면도: 0 mm; 작업 기준면: 레벨 : 지상 1층
구조 - 보강 철근 피복 - 다른 면: 보강 철근 피복 1 <25 mm>; 보강 철근 피복 - 하단 면: 보강 철근 피복 1 <25 mm>; 구조적 용도: 기타
기타 - 패밀리: BM111-철근콘크리트구조 보; 유형: BM110-철근 콘크리트구조 보_400 x 800_1B5; 유형 ID: 7667213; 패밀리 및 유형: BM111-철근콘크리트구조 보: BM110-철근 콘크리트구조 보_400 x 800_1B5
기하학적 위치 - yz 맞춤: 균일; y 간격띄우기 값: 0 mm; y 맞춤: 원점; z 맞춤: 상단; 결합 상태: 두 결합 모두 사용
치수 - 단면적: 0.32 m2
Name (BM111-철근콘크리트구조 보:BM110-철근 콘크리트구조 보_400 x 800_1B5:...) | Span (mm) = 길이 (mm) | CrossSectionArea (m2) | NetVolume (m3) = 체적 (m3) | 절단 길이 (mm) | z 간격띄우기 값 (mm) = 상단 기준 레벨 (mm) | 하단 기준 레벨 (mm)
7667185 | 6900 | 0.00376454 | 2.12163 | 7213.86 | -550 | -1350 | BaseQuantities - Length: 313.865 mm; OuterSurfaceArea: 0.0786488 m2; GrossSurfaceArea: 0.0861779 m2; GrossVolume: 0.00118156 m3; NetSurfaceArea: 17.1796 m2; 구조 - 보강 철근 피복 - 상단 면: 보강 철근 피복 1 <25 mm>
7667187 | 5800 | 6.17753 | 1.41836 | 5800 | -600 | -1400 | Material: KBIMS-콘크리트
7668330 | 6900 | 5.8897 | 0.39628 | 7100 | -550 | -1350 | BaseQuantities - NetSurfaceArea: 11.7794 m2; 구조 - 보강 철근 피복 - 상단 면: 보강 철근 피복 1 <25 mm>
7668332 | 5800 | 4.07765 | 0.268315 | 5800 | -600 | -1400 | Material: KBIMS-콘크리트

# IfcBeam: BM111-철근콘크리트구조 보:BM110-철근 콘크리트구조 보_400 x 800_B1-1B2 (4)
In: 지상 1층
Type - PredefinedType: BEAM; Material: KBIMS-콘크리트 (2)
Type - ID 데이터 - 유형 마크: B2; 유형 이름: BM110-철근 콘크리트구조 보_400 x 800_B1-1B2
Type - 구조 - 단면 모양: 0
Type - 기타 - 내화구조여부: yes; 주요구조부여부: yes; 카테고리: 구조 프레임; KBIMS-부위코드: E23; 제작정보: bSK-2021_KBIMS2.0-bC; 조달청표준공사코드: AD; 패밀리 이름: BM111-철근콘크리트구조 보
Type - 재료 및 마감재 - 구조 재료: KBIMS-콘크리트
Type - 치수 - 가로치수: 400 mm; 세로치수: 850 mm
Type - Pset_BeamCommon - IsExternal: no; LoadBearing: yes
Pset_BeamCommon - Slope: 0 deg; Reference: BM110-철근 콘크리트구조 보_400 x 800_B1-1B2
Pset_QuantityTakeOff - Reference: BM110-철근 콘크리트구조 보_400 x 800_B1-1B2; sets with these values: 2
ID 데이터 - 연관 있음: no
공정 - 생성 공정: 새 구성
구속조건 - 끝 레벨 간격띄우기: 0 mm; 단면형상 회전: 0 deg; 방향: 보통; 시작 레벨 간격띄우기: 0 mm; 참조 레벨: 지상 1층; 참조 레벨 입면도: 0 mm; 작업 기준면: 레벨 : 지상 1층
구조 - 보강 철근 피복 - 다른 면: 보강 철근 피복 1 <25 mm>; 보강 철근 피복 - 하단 면: 보강 철근 피복 1 <25 mm>
기타 - 패밀리: BM111-철근콘크리트구조 보; 유형: BM110-철근 콘크리트구조 보_400 x 800_B1-1B2; 유형 ID: 7667211; 패밀리 및 유형: BM111-철근콘크리트구조 보: BM110-철근 콘크리트구조 보_400 x 800_B1-1B2
기하학적 위치 - yz 맞춤: 균일; y 간격띄우기 값: 0 mm; y 맞춤: 원점; z 간격띄우기 값: 0 mm; z 맞춤: 상단; 결합 상태: 두 결합 모두 사용
치수 - 상단 기준 레벨: 0 mm; 단면적: 0.34 m2; 하단 기준 레벨: -850 mm
Name (BM111-철근콘크리트구조 보:BM110-철근 콘크리트구조 보_400 x 800_B1-1B2:...) | Span (mm) = 길이 (mm) | CrossSectionArea (m2) | NetVolume (m3) = 체적 (m3) | NetSurfaceArea (m2) | 구조적 용도 | 절단 길이 (mm)
7667156 | 8650 | 0.161007 | 2.32639 | 19.2741 | 거더 | 8650 | BaseQuantities - Length: 113.865 mm; OuterSurfaceArea: 0.182845 m2; GrossSurfaceArea: 0.504859 m2; GrossVolume: 0.018333 m3; 구조 - 보강 철근 피복 - 상단 면: 보강 철근 피복 1 <25 mm>
7667157 | 8650 | 5.77015 | 2.33083 | 19.3742 | 거더 | 8650 | BaseQuantities - Length: 400 mm; OuterSurfaceArea: 7.22891 m2; GrossSurfaceArea: 18.7692 m2; GrossVolume: 2.30806 m3; 구조 - 보강 철근 피복 - 상단 면: 보강 철근 피복 1 <25 mm>
7667171 | 8952 | 9.3043 | 2.22537 | 18.6086 | 기타 | 8564.68
7668315 | 8952 | 6.5827 | 0.629037 | 13.1654 | 기타 | 8497.02

# IfcBeam: BM111-철근콘크리트구조 보:BM110-철근 콘크리트구조 보_400 x 800_B1-1B2 (2)
In: 지상 1층
Type - PredefinedType: BEAM; Material: KBIMS-콘크리트 (3)
Type - ID 데이터 - 유형 마크: B2; 유형 이름: BM110-철근 콘크리트구조 보_400 x 800_B1-1B2
Type - 구조 - 단면 모양: 0
Type - 기타 - 내화구조여부: yes; 주요구조부여부: yes; 카테고리: 구조 프레임; KBIMS-부위코드: E23; 제작정보: bSK-2021_KBIMS2.0-bC; 조달청표준공사코드: AD; 패밀리 이름: BM111-철근콘크리트구조 보
Type - 재료 및 마감재 - 구조 재료: KBIMS-콘크리트
Type - 치수 - 가로치수: 400 mm; 세로치수: 850 mm
Type - Pset_BeamCommon - IsExternal: no; LoadBearing: yes
Pset_BeamCommon - Slope: 0 deg; Reference: BM110-철근 콘크리트구조 보_400 x 800_B1-1B2; Span: 8951 mm
Pset_QuantityTakeOff - Reference: BM110-철근 콘크리트구조 보_400 x 800_B1-1B2; sets with these values: 2
ID 데이터 - 연관 있음: no
공정 - 생성 공정: 새 구성
구속조건 - 끝 레벨 간격띄우기: 0 mm; 단면형상 회전: 0 deg; 방향: 보통; 시작 레벨 간격띄우기: 0 mm; 참조 레벨: 지상 1층; 참조 레벨 입면도: 0 mm; 작업 기준면: 레벨 : 지상 1층
구조 - 보강 철근 피복 - 다른 면: 보강 철근 피복 1 <25 mm>; 보강 철근 피복 - 하단 면: 보강 철근 피복 1 <25 mm>; 구조적 용도: 기타
기타 - 패밀리: BM111-철근콘크리트구조 보; 유형: BM110-철근 콘크리트구조 보_400 x 800_B1-1B2; 유형 ID: 7667211; 패밀리 및 유형: BM111-철근콘크리트구조 보: BM110-철근 콘크리트구조 보_400 x 800_B1-1B2
기하학적 위치 - yz 맞춤: 균일; y 간격띄우기 값: 0 mm; y 맞춤: 원점; z 간격띄우기 값: 0 mm; z 맞춤: 상단; 결합 상태: 두 결합 모두 사용
치수 - 상단 기준 레벨: 0 mm; 길이: 8951 mm; 단면적: 0.34 m2; 하단 기준 레벨: -850 mm
Name (BM111-철근콘크리트구조 보:BM110-철근 콘크리트구조 보_400 x 800_B1-1B2:...) | CrossSectionArea (m2) | NetVolume (m3) = 체적 (m3) | NetSurfaceArea (m2) | 절단 길이 (mm)
7667169 | 9.21767 | 2.10452 | 18.4353 | 8563.72
7668313 | 6.32815 | 0.593545 | 12.6563 | 8462.92

# IfcBeam: BM111-철근콘크리트구조 보:BM110-철근 콘크리트구조 보_400 x 800_B1-1B2 (16)
Type - ID 데이터 - 유형 마크: B2; 유형 이름: BM110-철근 콘크리트구조 보_400 x 800_B1-1B2
Type - 구조 - 단면 모양: 0
Type - 기타 - 내화구조여부: yes; 주요구조부여부: yes; 카테고리: 구조 프레임; KBIMS-부위코드: E23; 제작정보: bSK-2021_KBIMS2.0-bC; 조달청표준공사코드: AD; 패밀리 이름: BM111-철근콘크리트구조 보
Type - 재료 및 마감재 - 구조 재료: KBIMS-콘크리트
Type - 치수 - 가로치수: 400 mm; 세로치수: 850 mm
Type - Pset_BeamCommon - IsExternal: no; LoadBearing: yes
Material: KBIMS-콘크리트
Pset_BeamCommon - Slope: 0 deg; Reference: BM110-철근 콘크리트구조 보_400 x 800_B1-1B2
Pset_QuantityTakeOff - Reference: BM110-철근 콘크리트구조 보_400 x 800_B1-1B2; sets with these values: 2
ID 데이터 - 연관 있음: no
공정 - 생성 공정: 새 구성
구속조건 - 끝 레벨 간격띄우기: 0 mm; 단면형상 회전: 0 deg; 시작 레벨 간격띄우기: 0 mm
구조 - 보강 철근 피복 - 다른 면: 보강 철근 피복 1 <25 mm>; 보강 철근 피복 - 하단 면: 보강 철근 피복 1 <25 mm>; 구조적 용도: 거더
기타 - 패밀리: BM111-철근콘크리트구조 보; 유형: BM110-철근 콘크리트구조 보_400 x 800_B1-1B2; 유형 ID: 7667211; 패밀리 및 유형: BM111-철근콘크리트구조 보: BM110-철근 콘크리트구조 보_400 x 800_B1-1B2
기하학적 위치 - yz 맞춤: 균일; y 간격띄우기 값: 0 mm; y 맞춤: 원점; z 간격띄우기 값: 0 mm; z 맞춤: 상단; 결합 상태: 두 결합 모두 사용
치수 - 단면적: 0.34 m2
Name (BM111-철근콘크리트구조 보:BM110-철근 콘크리트구조 보_400 x 800_B1-1B2:...) | In | CrossSectionArea (m2) | NetVolume (m3) = 체적 (m3) | Span (mm) = 길이 (mm) | 참조 레벨 | 참조 레벨 입면도 (mm) = 상단 기준 레벨 (mm) | 절단 길이 (mm) | 하단 기준 레벨 (mm) | 방향 | 작업 기준면
7667149 | 지상 1층 | 0.28 | 2.282 | 8650 | 지상 1층 | 0 | 8150 | -850
7667150 | 지상 1층 | 0.28 | 2.282 | 8650 | 지상 1층 | 0 | 8150 | -850
7667153 | 지상 1층 | 0.28 | 2.282 | 8650 | 지상 1층 | 0 | 8150 | -850 | 보통 | 레벨 : 지상 1층
7667154 | 지상 1층 | 0.28 | 2.282 | 8650 | 지상 1층 | 0 | 8150 | -850 | 보통 | 레벨 : 지상 1층
7668195 | 지하1층 | 0.28 | 2.254 | 8550 | 지하1층 | -6100 | 8050 | -6950 | 보통 | 레벨 : 지하1층
7668196 | 지하1층 | 0.28 | 2.254 | 8550 | 지하1층 | -6100 | 8050 | -6950 | 보통 | 레벨 : 지하1층
7668199 | 지하1층 | 0.28 | 2.24 | 8500 | 지하1층 | -6100 | 8000 | -6950 | 보통 | 레벨 : 지하1층
7668200 | 지하1층 | 0.28 | 2.24 | 8500 | 지하1층 | -6100 | 8000 | -6950 | 보통 | 레벨 : 지하1층
7668202 | 지하1층 | 0.28 | 2.24 | 8500 | 지하1층 | -6100 | 8000 | -6950 | 보통 | 레벨 : 지하1층
7668203 | 지하1층 | 0.28 | 2.24 | 8500 | 지하1층 | -6100 | 8000 | -6950 | 보통 | 레벨 : 지하1층
7668287 | 지상 1층 | 0.0527096 | 0.423582 | 8650 | 지상 1층 | 0 | 8036.14 | -850
7668288 | 지상 1층 | 0.0527096 | 0.423582 | 8650 | 지상 1층 | 0 | 8036.14 | -850
7668291 | 지상 1층 | 0.0527096 | 0.423582 | 8650 | 지상 1층 | 0 | 8036.14 | -850 | 보통 | 레벨 : 지상 1층
7668292 | 지상 1층 | 0.0527096 | 0.423582 | 8650 | 지상 1층 | 0 | 8036.14 | -850 | 보통 | 레벨 : 지상 1층
7668294 | 지상 1층 | 0.0527096 | 0.423582 | 8650 | 지상 1층 | 0 | 8036.14 | -850 | 보통 | 레벨 : 지상 1층
7668295 | 지상 1층 | 0.0527096 | 0.423582 | 8650 | 지상 1층 | 0 | 8036.14 | -850 | 보통 | 레벨 : 지상 1층

# IfcBeam: BM111-철근콘크리트구조 보:BM110-철근 콘크리트구조 보_400 x 800_B1B3, BM111-철근콘크리트구조 보:BM110-철근 콘크리트구조 보_400 x 800_B1B3:7668226
In: 지하1층
Type - ID 데이터 - 유형 마크: B3; 유형 이름: BM110-철근 콘크리트구조 보_400 x 800_B1B3
Type - 구조 - 단면 모양: 0
Type - 기타 - 내화구조여부: yes; 주요구조부여부: yes; 카테고리: 구조 프레임; KBIMS-부위코드: E23; 제작정보: bSK-2021_KBIMS2.0-bC; 조달청표준공사코드: AD; 패밀리 이름: BM111-철근콘크리트구조 보
Type - 재료 및 마감재 - 구조 재료: KBIMS-콘크리트
Type - 치수 - 가로치수: 400 mm; 세로치수: 800 mm
Type - Pset_BeamCommon - IsExternal: no; LoadBearing: yes
Material: KBIMS-콘크리트
BaseQuantities - CrossSectionArea: 10.3902 m2; NetVolume: 2.15427 m3
Pset_BeamCommon - Slope: 0 deg; Reference: BM110-철근 콘크리트구조 보_400 x 800_B1B3; Span: 8800 mm
Pset_QuantityTakeOff - Reference: BM110-철근 콘크리트구조 보_400 x 800_B1B3; sets with these values: 2
ID 데이터 - 연관 있음: no
공정 - 생성 공정: 새 구성
구속조건 - 끝 레벨 간격띄우기: 0 mm; 단면형상 회전: 0 deg; 방향: 보통; 시작 레벨 간격띄우기: 0 mm; 참조 레벨: 지하1층; 작업 기준면: 레벨 : 지하1층; 참조 레벨 입면도: -6100 mm
구조 - 보강 철근 피복 - 다른 면: 보강 철근 피복 1 <25 mm>; 보강 철근 피복 - 상단 면: 보강 철근 피복 1 <25 mm>; 보강 철근 피복 - 하단 면: 보강 철근 피복 1 <25 mm>; 구조적 용도: 기타; 절단 길이: 8899.99 mm
기타 - 패밀리: BM111-철근콘크리트구조 보; 유형: BM110-철근 콘크리트구조 보_400 x 800_B1B3; 유형 ID: 7669401; 패밀리 및 유형: BM111-철근콘크리트구조 보: BM110-철근 콘크리트구조 보_400 x 800_B1B3
기하학적 위치 - yz 맞춤: 균일; y 간격띄우기 값: 0 mm; y 맞춤: 원점; z 간격띄우기 값: 0 mm; z 맞춤: 상단; 결합 상태: 두 결합 모두 사용
치수 - 길이: 8800 mm; 단면적: 0.32 m2; 상단 기준 레벨: -6100 mm; 체적: 2.15427 m3; 하단 기준 레벨: -6900 mm

# IfcBeam: BM111-철근콘크리트구조 보:BM110-철근 콘크리트구조 보_400 x 850_-1WG1, BM111-철근콘크리트구조 보:BM110-철근 콘크리트구조 보_400 x 850_-1WG1:7669300
In: 지하1층
Type - PredefinedType: BEAM; Material: KBIMS-콘크리트 (2)
Type - ID 데이터 - 유형 마크: WG1; 유형 이름: BM110-철근 콘크리트구조 보_400 x 850_-1WG1
Type - 구조 - 단면 모양: 0
Type - 기타 - 내화구조여부: yes; 주요구조부여부: yes; 카테고리: 구조 프레임; KBIMS-부위코드: E23; 제작정보: bSK-2021_KBIMS2.0-bC; 조달청표준공사코드: AD; 패밀리 이름: BM111-철근콘크리트구조 보
Type - 재료 및 마감재 - 구조 재료: KBIMS-콘크리트
Type - 치수 - 가로치수: 400 mm; 세로치수: 850 mm
Type - Pset_BeamCommon - IsExternal: no; LoadBearing: yes
Pset_BeamCommon - Slope: 0 deg; Reference: BM110-철근 콘크리트구조 보_400 x 850_-1WG1; Span: 13300 mm
Pset_QuantityTakeOff - Reference: BM110-철근 콘크리트구조 보_400 x 850_-1WG1; sets with these values: 2
BaseQuantities - Length: 4000.01 mm; CrossSectionArea: 0.129994 m2; OuterSurfaceArea: 6.79994 m2; GrossSurfaceArea: 7.05993 m2; GrossVolume: 0.519976 m3; NetVolume: 1.67075 m3; NetSurfaceArea: 22.6258 m2
ID 데이터 - 연관 있음: no
공정 - 생성 공정: 새 구성
구속조건 - 끝 레벨 간격띄우기: 0 mm; 단면형상 회전: 0 deg; 방향: 보통; 시작 레벨 간격띄우기: 0 mm; 참조 레벨: 지하1층; 작업 기준면: 레벨 : 지하1층; 참조 레벨 입면도: -6100 mm
구조 - 보강 철근 피복 - 다른 면: 보강 철근 피복 1 <25 mm>; 보강 철근 피복 - 하단 면: 보강 철근 피복 1 <25 mm>; 구조적 용도: 거더; 절단 길이: 13500 mm
기타 - 패밀리: BM111-철근콘크리트구조 보; 유형: BM110-철근 콘크리트구조 보_400 x 850_-1WG1; 유형 ID: 7669395; 패밀리 및 유형: BM111-철근콘크리트구조 보: BM110-철근 콘크리트구조 보_400 x 850_-1WG1
기하학적 위치 - yz 맞춤: 균일; y 간격띄우기 값: 0 mm; y 맞춤: 원점; z 간격띄우기 값: 0 mm; z 맞춤: 상단; 결합 상태: 두 결합 모두 사용
치수 - 길이: 13300 mm; 단면적: 0.34 m2; 상단 기준 레벨: -6100 mm; 체적: 1.67075 m3; 하단 기준 레벨: -6950 mm

# IfcBeam: BM111-철근콘크리트구조 보:BM110-철근 콘크리트구조 보_400 x 850_-1WG1, BM111-철근콘크리트구조 보:BM110-철근 콘크리트구조 보_400 x 850_-1WG1:7669298
In: 지하1층
Type - PredefinedType: BEAM; Material: KBIMS-콘크리트 (7)
Type - ID 데이터 - 유형 마크: WG1; 유형 이름: BM110-철근 콘크리트구조 보_400 x 850_-1WG1
Type - 구조 - 단면 모양: 0
Type - 기타 - 내화구조여부: yes; 주요구조부여부: yes; 카테고리: 구조 프레임; KBIMS-부위코드: E23; 제작정보: bSK-2021_KBIMS2.0-bC; 조달청표준공사코드: AD; 패밀리 이름: BM111-철근콘크리트구조 보
Type - 재료 및 마감재 - 구조 재료: KBIMS-콘크리트
Type - 치수 - 가로치수: 400 mm; 세로치수: 850 mm
Type - Pset_BeamCommon - IsExternal: no; LoadBearing: yes
Pset_BeamCommon - Slope: 0 deg; Reference: BM110-철근 콘크리트구조 보_400 x 850_-1WG1; Span: 13358 mm
Pset_QuantityTakeOff - Reference: BM110-철근 콘크리트구조 보_400 x 850_-1WG1; sets with these values: 2
BaseQuantities - Length: 2500 mm; CrossSectionArea: 0.00156158 m2; OuterSurfaceArea: 4.25919 m2; GrossSurfaceArea: 4.26231 m2; GrossVolume: 0.00390394 m3; NetVolume: 1.85552 m3; NetSurfaceArea: 44.3054 m2
ID 데이터 - 연관 있음: no
공정 - 생성 공정: 새 구성
구속조건 - 끝 레벨 간격띄우기: 0 mm; 단면형상 회전: 0 deg; 방향: 보통; 시작 레벨 간격띄우기: 0 mm; 참조 레벨: 지하1층; 작업 기준면: 레벨 : 지하1층; 참조 레벨 입면도: -6100 mm
구조 - 보강 철근 피복 - 다른 면: 보강 철근 피복 1 <25 mm>; 보강 철근 피복 - 상단 면: 보강 철근 피복 1 <25 mm>; 보강 철근 피복 - 하단 면: 보강 철근 피복 1 <25 mm>; 구조적 용도: 거더; 절단 길이: 13277.2 mm
기타 - 패밀리: BM111-철근콘크리트구조 보; 유형: BM110-철근 콘크리트구조 보_400 x 850_-1WG1; 유형 ID: 7669395; 패밀리 및 유형: BM111-철근콘크리트구조 보: BM110-철근 콘크리트구조 보_400 x 850_-1WG1
기하학적 위치 - yz 맞춤: 균일; y 간격띄우기 값: 0 mm; y 맞춤: 원점; z 간격띄우기 값: 0 mm; z 맞춤: 상단; 결합 상태: 두 결합 모두 사용
치수 - 길이: 13358 mm; 단면적: 0.34 m2; 상단 기준 레벨: -6100 mm; 체적: 1.85552 m3; 하단 기준 레벨: -6950 mm

# IfcBeam: BM111-철근콘크리트구조 보:BM110-철근 콘크리트구조 보_400 x 850_-1WG1 (3)
In: 지하1층
Type - ID 데이터 - 유형 마크: WG1; 유형 이름: BM110-철근 콘크리트구조 보_400 x 850_-1WG1
Type - 구조 - 단면 모양: 0
Type - 기타 - 내화구조여부: yes; 주요구조부여부: yes; 카테고리: 구조 프레임; KBIMS-부위코드: E23; 제작정보: bSK-2021_KBIMS2.0-bC; 조달청표준공사코드: AD; 패밀리 이름: BM111-철근콘크리트구조 보
Type - 재료 및 마감재 - 구조 재료: KBIMS-콘크리트
Type - 치수 - 가로치수: 400 mm; 세로치수: 850 mm
Type - Pset_BeamCommon - IsExternal: no; LoadBearing: yes
Material: KBIMS-콘크리트
Pset_BeamCommon - Slope: 0 deg; Reference: BM110-철근 콘크리트구조 보_400 x 850_-1WG1
Pset_QuantityTakeOff - Reference: BM110-철근 콘크리트구조 보_400 x 850_-1WG1; sets with these values: 2
ID 데이터 - 연관 있음: no
공정 - 생성 공정: 새 구성
구속조건 - 끝 레벨 간격띄우기: 0 mm; 단면형상 회전: 0 deg; 시작 레벨 간격띄우기: 0 mm; 참조 레벨: 지하1층; 작업 기준면: 레벨 : 지하1층; 참조 레벨 입면도: -6100 mm
구조 - 보강 철근 피복 - 다른 면: 보강 철근 피복 1 <25 mm>; 보강 철근 피복 - 하단 면: 보강 철근 피복 1 <25 mm>
기타 - 패밀리: BM111-철근콘크리트구조 보; 유형: BM110-철근 콘크리트구조 보_400 x 850_-1WG1; 유형 ID: 7669395; 패밀리 및 유형: BM111-철근콘크리트구조 보: BM110-철근 콘크리트구조 보_400 x 850_-1WG1
기하학적 위치 - yz 맞춤: 균일; y 간격띄우기 값: 0 mm; y 맞춤: 원점; z 간격띄우기 값: 0 mm; z 맞춤: 상단; 결합 상태: 두 결합 모두 사용
치수 - 단면적: 0.34 m2; 상단 기준 레벨: -6100 mm; 하단 기준 레벨: -6950 mm
Name (BM111-철근콘크리트구조 보:BM110-철근 콘크리트구조 보_400 x 850_-1WG1:...) | CrossSectionArea (m2) | NetVolume (m3) = 체적 (m3) | Span (mm) = 길이 (mm) | 구조적 용도 | 절단 길이 (mm) | 방향
7669297 | 0.0707314 | 0.00225467 | 8766 | 기타 | 116.013
7669299 | 0.140006 | 1.49806 | 11100 | 거더 | 10700 | 보통
7669301 | 5.10242 | 0.684997 | 5000 | 기타 | 4599.99 | 보통 | 구조 - 끝 부착 유형: 끝 입면

# IfcBeam: BM111-철근콘크리트구조 보:BM110-철근 콘크리트구조 보_400 x 850_1WG2, BM111-철근콘크리트구조 보:BM110-철근 콘크리트구조 보_400 x 850_1WG2:7667188
In: 지상 1층
Type - PredefinedType: BEAM; Material: KBIMS-콘크리트 (3)
Type - ID 데이터 - 유형 마크: WG2; 유형 이름: BM110-철근 콘크리트구조 보_400 x 850_1WG2
Type - 구조 - 단면 모양: 0
Type - 기타 - 내화구조여부: yes; 주요구조부여부: yes; 카테고리: 구조 프레임; KBIMS-부위코드: E23; 제작정보: bSK-2021_KBIMS2.0-bC; 조달청표준공사코드: AD; 패밀리 이름: BM111-철근콘크리트구조 보
Type - 재료 및 마감재 - 구조 재료: KBIMS-콘크리트
Type - 치수 - 가로치수: 400 mm; 세로치수: 850 mm
Type - Pset_BeamCommon - IsExternal: no; LoadBearing: yes
Pset_BeamCommon - Slope: 0 deg; Reference: BM110-철근 콘크리트구조 보_400 x 850_1WG2; Span: 8125 mm
Pset_QuantityTakeOff - Reference: BM110-철근 콘크리트구조 보_400 x 850_1WG2; sets with these values: 2
BaseQuantities - Length: 122.88 mm; CrossSectionArea: 0.22 m2; OuterSurfaceArea: 0.233472 m2; GrossSurfaceArea: 0.673472 m2; GrossVolume: 0.0270336 m3; NetVolume: 2.38029 m3; NetSurfaceArea: 19.9612 m2
ID 데이터 - 연관 있음: no
공정 - 생성 공정: 새 구성
구속조건 - 끝 레벨 간격띄우기: 0 mm; 단면형상 회전: 0 deg; 방향: 보통; 시작 레벨 간격띄우기: 0 mm; 참조 레벨: 지상 1층; 참조 레벨 입면도: 0 mm; 작업 기준면: 레벨 : 지상 1층
구조 - 보강 철근 피복 - 다른 면: 보강 철근 피복 1 <25 mm>; 보강 철근 피복 - 상단 면: 보강 철근 피복 1 <25 mm>; 보강 철근 피복 - 하단 면: 보강 철근 피복 1 <25 mm>; 구조적 용도: 기타; 절단 길이: 8424.73 mm
기타 - 패밀리: BM111-철근콘크리트구조 보; 유형: BM110-철근 콘크리트구조 보_400 x 850_1WG2; 유형 ID: 7667208; 패밀리 및 유형: BM111-철근콘크리트구조 보: BM110-철근 콘크리트구조 보_400 x 850_1WG2
기하학적 위치 - yz 맞춤: 균일; y 간격띄우기 값: 0 mm; y 맞춤: 원점; z 맞춤: 상단; 결합 상태: 두 결합 모두 사용; z 간격띄우기 값: -550 mm
치수 - 길이: 8125 mm; 단면적: 0.34 m2; 상단 기준 레벨: -550 mm; 체적: 2.38029 m3; 하단 기준 레벨: -1400 mm

# IfcBeam: BM111-철근콘크리트구조 보:BM110-철근 콘크리트구조 보_400 x 850_1WG2, BM111-철근콘크리트구조 보:BM110-철근 콘크리트구조 보_400 x 850_1WG2:7668333
In: 지상 1층
Type - PredefinedType: BEAM; Material: KBIMS-콘크리트 (4)
Type - ID 데이터 - 유형 마크: WG2; 유형 이름: BM110-철근 콘크리트구조 보_400 x 850_1WG2
Type - 구조 - 단면 모양: 0
Type - 기타 - 내화구조여부: yes; 주요구조부여부: yes; 카테고리: 구조 프레임; KBIMS-부위코드: E23; 제작정보: bSK-2021_KBIMS2.0-bC; 조달청표준공사코드: AD; 패밀리 이름: BM111-철근콘크리트구조 보
Type - 재료 및 마감재 - 구조 재료: KBIMS-콘크리트
Type - 치수 - 가로치수: 400 mm; 세로치수: 850 mm
Type - Pset_BeamCommon - IsExternal: no; LoadBearing: yes
Pset_BeamCommon - Slope: 0 deg; Reference: BM110-철근 콘크리트구조 보_400 x 850_1WG2; Span: 8200 mm
Pset_QuantityTakeOff - Reference: BM110-철근 콘크리트구조 보_400 x 850_1WG2; sets with these values: 2
BaseQuantities - CrossSectionArea: 5.94426 m2; NetVolume: 0.182246 m3; NetSurfaceArea: 11.8885 m2
ID 데이터 - 연관 있음: no
공정 - 생성 공정: 새 구성
구속조건 - 끝 레벨 간격띄우기: 0 mm; 단면형상 회전: 0 deg; 방향: 보통; 시작 레벨 간격띄우기: 0 mm; 참조 레벨: 지상 1층; 참조 레벨 입면도: 0 mm; 작업 기준면: 레벨 : 지상 1층
구조 - 보강 철근 피복 - 다른 면: 보강 철근 피복 1 <25 mm>; 보강 철근 피복 - 상단 면: 보강 철근 피복 1 <25 mm>; 보강 철근 피복 - 하단 면: 보강 철근 피복 1 <25 mm>; 구조적 용도: 기타; 절단 길이: 8500.03 mm
기타 - 패밀리: BM111-철근콘크리트구조 보; 유형: BM110-철근 콘크리트구조 보_400 x 850_1WG2; 유형 ID: 7667208; 패밀리 및 유형: BM111-철근콘크리트구조 보: BM110-철근 콘크리트구조 보_400 x 850_1WG2
기하학적 위치 - yz 맞춤: 균일; y 간격띄우기 값: 0 mm; y 맞춤: 원점; z 맞춤: 상단; 결합 상태: 두 결합 모두 사용; z 간격띄우기 값: -550 mm
치수 - 길이: 8200 mm; 단면적: 0.34 m2; 상단 기준 레벨: -550 mm; 체적: 0.182246 m3; 하단 기준 레벨: -1400 mm

# IfcBeam: BM111-철근콘크리트구조 보:BM110-철근 콘크리트구조 보_400 x 850_B1-1B1 (11)
Type - PredefinedType: BEAM; Material: KBIMS-콘크리트
Type - ID 데이터 - 유형 마크: B1; 유형 이름: BM110-철근 콘크리트구조 보_400 x 850_B1-1B1
Type - 구조 - 단면 모양: 0
Type - 기타 - 내화구조여부: yes; 주요구조부여부: yes; 카테고리: 구조 프레임; KBIMS-부위코드: E23; 제작정보: bSK-2021_KBIMS2.0-bC; 조달청표준공사코드: AD; 패밀리 이름: BM111-철근콘크리트구조 보
Type - 재료 및 마감재 - 구조 재료: KBIMS-콘크리트
Type - 치수 - 가로치수: 400 mm; 세로치수: 850 mm
Type - Pset_BeamCommon - IsExternal: no; LoadBearing: yes
Pset_BeamCommon - Slope: 0 deg; Reference: BM110-철근 콘크리트구조 보_400 x 850_B1-1B1
Pset_QuantityTakeOff - Reference: BM110-철근 콘크리트구조 보_400 x 850_B1-1B1; sets with these values: 2
ID 데이터 - 연관 있음: no
공정 - 생성 공정: 새 구성
구속조건 - 끝 레벨 간격띄우기: 0 mm; 단면형상 회전: 0 deg; 방향: 보통; 시작 레벨 간격띄우기: 0 mm
구조 - 보강 철근 피복 - 다른 면: 보강 철근 피복 1 <25 mm>; 보강 철근 피복 - 하단 면: 보강 철근 피복 1 <25 mm>; 구조적 용도: 기타
기타 - 패밀리: BM111-철근콘크리트구조 보; 유형: BM110-철근 콘크리트구조 보_400 x 850_B1-1B1; 유형 ID: 7667210; 패밀리 및 유형: BM111-철근콘크리트구조 보: BM110-철근 콘크리트구조 보_400 x 850_B1-1B1
기하학적 위치 - yz 맞춤: 균일; y 간격띄우기 값: 0 mm; y 맞춤: 원점; z 맞춤: 상단; 결합 상태: 두 결합 모두 사용
치수 - 단면적: 0.34 m2
Name (BM111-철근콘크리트구조 보:BM110-철근 콘크리트구조 보_400 x 850_B1-1B1:...) | In | Span (mm) = 길이 (mm) | CrossSectionArea (m2) | NetVolume (m3) = 체적 (m3) | 참조 레벨 | 참조 레벨 입면도 (mm) | 작업 기준면 | 절단 길이 (mm) | z 간격띄우기 값 (mm) | 상단 기준 레벨 (mm) | 하단 기준 레벨 (mm)
7667164 | 지상 1층 | 10275 | 0.28 | 2.73708 | 지상 1층 | 0 | 레벨 : 지상 1층 | 10175.3 | -500 | -500 | -1350 | BaseQuantities - Length: 75.2908 mm; OuterSurfaceArea: 0.16564 m2; GrossSurfaceArea: 0.72564 m2; GrossVolume: 0.0210814 m3; NetSurfaceArea: 22.6257 m2
7667165 | 지상 1층 | 9200 | 0.28 | 2.4639 | 지상 1층 | 0 | 레벨 : 지상 1층 | 8799.63 | 0 | 0 | -850 | 구조 - 보강 철근 피복 - 상단 면: 보강 철근 피복 1 <25 mm>
7668209 | 지하1층 | 9900 | 0.28 | 2.66 | 지하1층 | -6100 | 레벨 : 지하1층 | 9500 | 0 | -6100 | -6950
7668210 | 지하1층 | 9000 | 0.28 | 2.408 | 지하1층 | -6100 | 레벨 : 지하1층 | 8600.01 | 0 | -6100 | -6950
7668215 | 지하1층 | 10000 | 0.28 | 2.66 | 지하1층 | -6100 | 레벨 : 지하1층 | 9499.99 | 0 | -6100 | -6950
7668216 | 지하1층 | 10000 | 0.28 | 2.66 | 지하1층 | -6100 | 레벨 : 지하1층 | 9499.99 | 0 | -6100 | -6950
7668221 | 지하1층 | 9900 | 9.93224 | 2.3409 | 지하1층 | -6100 | 레벨 : 지하1층 | 9500 | 0 | -6100 | -6950
7668302 | 지상 1층 | 10200 | 0.0797051 | 0.767139 | 지상 1층 | 0 | 레벨 : 지상 1층 | 9624.71 | -500 | -500 | -1350
7668303 | 지상 1층 | 9200 | 0.0797051 | 0.695374 | 지상 1층 | 0 | 레벨 : 지상 1층 | 8724.33 | 0 | 0 | -850
7668308 | 지상 1층 | 10100 | 0.28 | 2.688 | 지상 1층 | 0 | 레벨 : 지상 1층 | 9600.01 | -1500 | -1500 | -2350
7668309 | 지상 1층 | 10100 | 0.28 | 2.688 | 지상 1층 | 0 | 레벨 : 지상 1층 | 9600.01 | -1500 | -1500 | -2350

# IfcBeam: BM111-철근콘크리트구조 보:BM110-철근 콘크리트구조 보_400 x 850_B1-1B1, BM111-철근콘크리트구조 보:BM110-철근 콘크리트구조 보_400 x 850_B1-1B1:7668224
In: 지하1층
Type - PredefinedType: BEAM; Material: KBIMS-콘크리트 (2)
Type - ID 데이터 - 유형 마크: B1; 유형 이름: BM110-철근 콘크리트구조 보_400 x 850_B1-1B1
Type - 구조 - 단면 모양: 0
Type - 기타 - 내화구조여부: yes; 주요구조부여부: yes; 카테고리: 구조 프레임; KBIMS-부위코드: E23; 제작정보: bSK-2021_KBIMS2.0-bC; 조달청표준공사코드: AD; 패밀리 이름: BM111-철근콘크리트구조 보
Type - 재료 및 마감재 - 구조 재료: KBIMS-콘크리트
Type - 치수 - 가로치수: 400 mm; 세로치수: 850 mm
Type - Pset_BeamCommon - IsExternal: no; LoadBearing: yes
Pset_BeamCommon - Slope: 0 deg; Reference: BM110-철근 콘크리트구조 보_400 x 850_B1-1B1; Span: 7875 mm
Pset_QuantityTakeOff - Reference: BM110-철근 콘크리트구조 보_400 x 850_B1-1B1; sets with these values: 2
BaseQuantities - CrossSectionArea: 8.39773 m2; NetVolume: 1.96197 m3; NetSurfaceArea: 16.7955 m2
ID 데이터 - 연관 있음: no
공정 - 생성 공정: 새 구성
구속조건 - 끝 레벨 간격띄우기: 0 mm; 단면형상 회전: 0 deg; 방향: 보통; 시작 레벨 간격띄우기: 0 mm; 참조 레벨: 지하1층; 작업 기준면: 레벨 : 지하1층; 참조 레벨 입면도: -6100 mm
구조 - 보강 철근 피복 - 다른 면: 보강 철근 피복 1 <25 mm>; 보강 철근 피복 - 상단 면: 보강 철근 피복 1 <25 mm>; 보강 철근 피복 - 하단 면: 보강 철근 피복 1 <25 mm>; 구조적 용도: 기타; 절단 길이: 7449.66 mm
기타 - 패밀리: BM111-철근콘크리트구조 보; 유형: BM110-철근 콘크리트구조 보_400 x 850_B1-1B1; 유형 ID: 7667210; 패밀리 및 유형: BM111-철근콘크리트구조 보: BM110-철근 콘크리트구조 보_400 x 850_B1-1B1
기하학적 위치 - yz 맞춤: 균일; y 간격띄우기 값: 0 mm; y 맞춤: 원점; z 간격띄우기 값: 0 mm; z 맞춤: 상단; 결합 상태: 두 결합 모두 사용
치수 - 길이: 7875 mm; 단면적: 0.34 m2; 상단 기준 레벨: -6100 mm; 체적: 1.96197 m3; 하단 기준 레벨: -6950 mm

# IfcBeam: BM111-철근콘크리트구조 보:BM110-철근 콘크리트구조 보_400 x 850_B1-1G1, BM111-철근콘크리트구조 보:BM110-철근 콘크리트구조 보_400 x 850_B1-1G1:7667130
In: 지상 1층
Type - PredefinedType: BEAM; Material: KBIMS-콘크리트
Type - ID 데이터 - 유형 마크: G1; 유형 이름: BM110-철근 콘크리트구조 보_400 x 850_B1-1G1
Type - 구조 - 단면 모양: 0
Type - 기타 - 내화구조여부: yes; 주요구조부여부: yes; 카테고리: 구조 프레임; KBIMS-부위코드: E23; 제작정보: bSK-2021_KBIMS2.0-bC; 조달청표준공사코드: AD; 패밀리 이름: BM111-철근콘크리트구조 보
Type - 재료 및 마감재 - 구조 재료: KBIMS-콘크리트
Type - 치수 - 가로치수: 400 mm; 세로치수: 850 mm
Type - Pset_BeamCommon - IsExternal: no; LoadBearing: yes
Pset_BeamCommon - Slope: 0 deg; Reference: BM110-철근 콘크리트구조 보_400 x 850_B1-1G1; Span: 9100 mm
Pset_QuantityTakeOff - Reference: BM110-철근 콘크리트구조 보_400 x 850_B1-1G1; sets with these values: 2
BaseQuantities - Length: 75.2908 mm; CrossSectionArea: 0.26 m2; OuterSurfaceArea: 0.158111 m2; GrossSurfaceArea: 0.678111 m2; GrossVolume: 0.0195756 m3; NetVolume: 2.54965 m3; NetSurfaceArea: 21.1173 m2
ID 데이터 - 연관 있음: no
공정 - 생성 공정: 새 구성
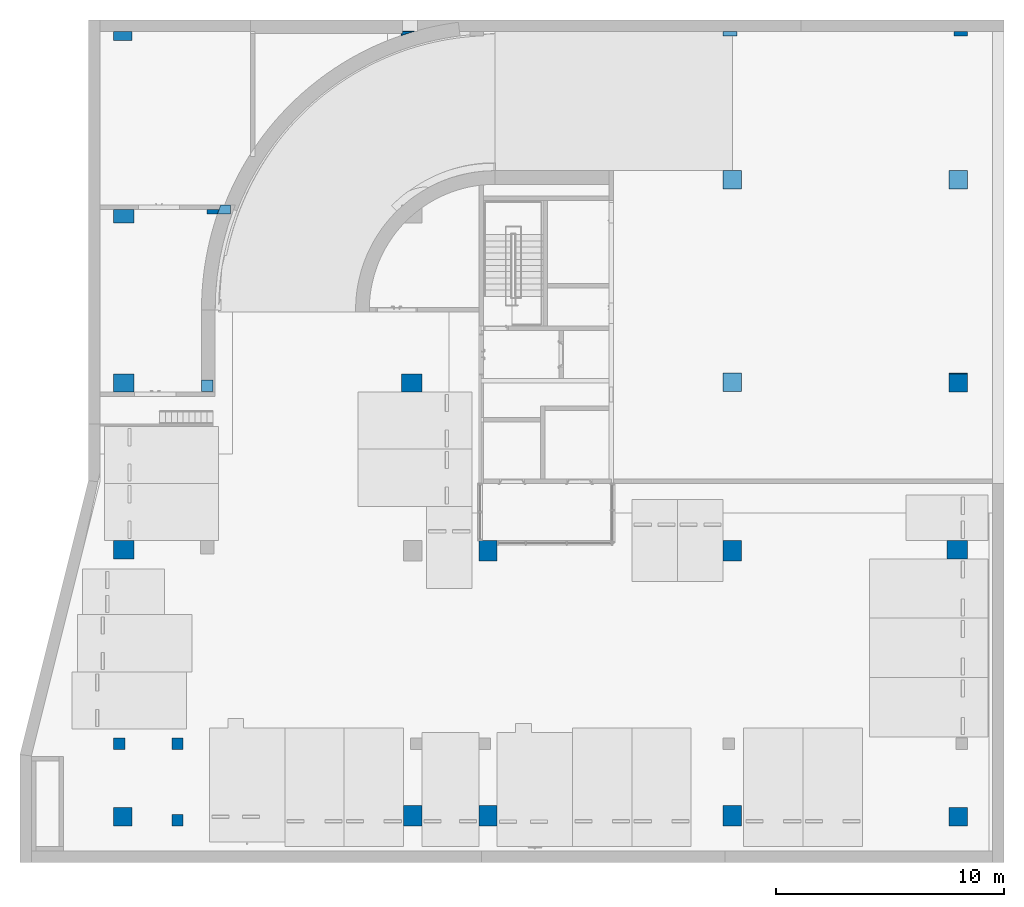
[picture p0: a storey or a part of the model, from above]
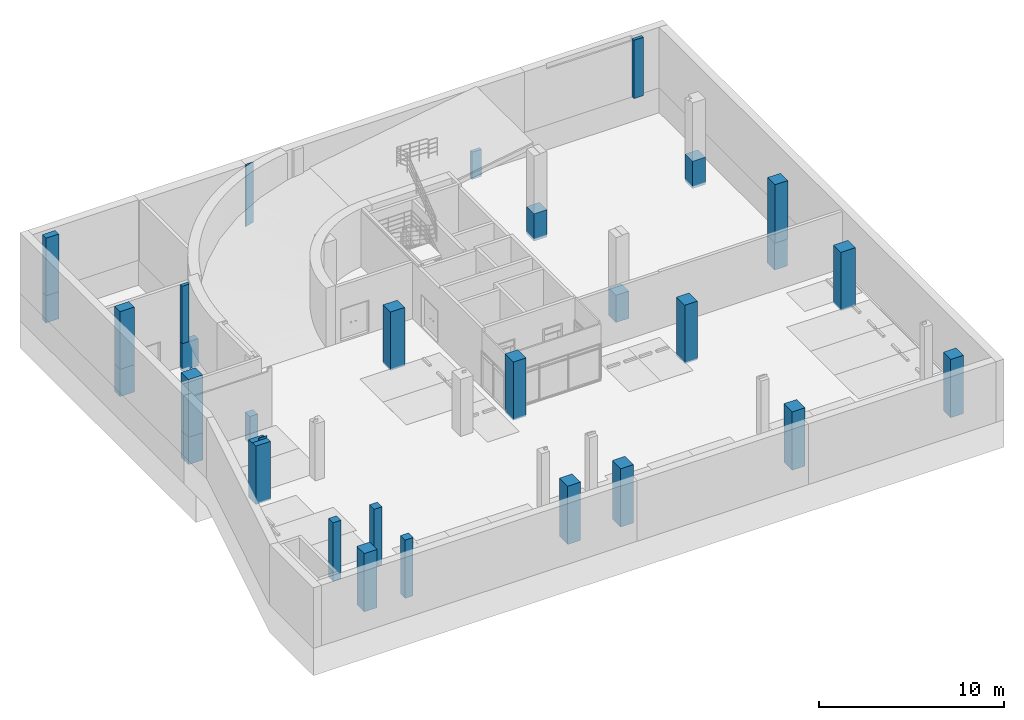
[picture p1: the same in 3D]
Properties of the parts of a building model (IFC2X3), part 8 of 39

# IfcBeam: BM111-철근콘크리트구조 보:BM110-철근 콘크리트구조 보_400 x 850_B1-1G1, BM111-철근콘크리트구조 보:BM110-철근 콘크리트구조 보_400 x 850_B1-1G1:7667130
구속조건 - 끝 레벨 간격띄우기: 0 mm; 단면형상 회전: 0 deg; 방향: 보통; 시작 레벨 간격띄우기: 0 mm; 참조 레벨: 지상 1층; 참조 레벨 입면도: 0 mm; 작업 기준면: 레벨 : 지상 1층
구조 - 보강 철근 피복 - 다른 면: 보강 철근 피복 1 <25 mm>; 보강 철근 피복 - 하단 면: 보강 철근 피복 1 <25 mm>; 구조적 용도: 기타; 시작 부착 유형: 끝 입면; 절단 길이: 9911.27 mm
기타 - 패밀리: BM111-철근콘크리트구조 보; 유형: BM110-철근 콘크리트구조 보_400 x 850_B1-1G1; 유형 ID: 7667209; 패밀리 및 유형: BM111-철근콘크리트구조 보: BM110-철근 콘크리트구조 보_400 x 850_B1-1G1
기하학적 위치 - yz 맞춤: 균일; y 간격띄우기 값: 0 mm; y 맞춤: 원점; z 간격띄우기 값: 0 mm; z 맞춤: 상단; 결합 상태: 두 결합 모두 사용
치수 - 상단 기준 레벨: 0 mm; 길이: 9100 mm; 단면적: 0.34 m2; 체적: 2.54965 m3; 하단 기준 레벨: -850 mm

# IfcBeam: BM111-철근콘크리트구조 보:BM110-철근 콘크리트구조 보_400 x 850_B1-1G1 (14)
Type - ID 데이터 - 유형 마크: G1; 유형 이름: BM110-철근 콘크리트구조 보_400 x 850_B1-1G1
Type - 구조 - 단면 모양: 0
Type - 기타 - 내화구조여부: yes; 주요구조부여부: yes; 카테고리: 구조 프레임; KBIMS-부위코드: E23; 제작정보: bSK-2021_KBIMS2.0-bC; 조달청표준공사코드: AD; 패밀리 이름: BM111-철근콘크리트구조 보
Type - 재료 및 마감재 - 구조 재료: KBIMS-콘크리트
Type - 치수 - 가로치수: 400 mm; 세로치수: 850 mm
Type - Pset_BeamCommon - IsExternal: no; LoadBearing: yes
Material: KBIMS-콘크리트
Pset_BeamCommon - Slope: 0 deg; Reference: BM110-철근 콘크리트구조 보_400 x 850_B1-1G1
Pset_QuantityTakeOff - Reference: BM110-철근 콘크리트구조 보_400 x 850_B1-1G1; sets with these values: 2
ID 데이터 - 연관 있음: no
공정 - 생성 공정: 새 구성
구속조건 - 끝 레벨 간격띄우기: 0 mm; 단면형상 회전: 0 deg; 시작 레벨 간격띄우기: 0 mm
구조 - 보강 철근 피복 - 다른 면: 보강 철근 피복 1 <25 mm>; 보강 철근 피복 - 하단 면: 보강 철근 피복 1 <25 mm>; 구조적 용도: 기타; 끝 부착 유형: 끝 입면
기타 - 패밀리: BM111-철근콘크리트구조 보; 유형: BM110-철근 콘크리트구조 보_400 x 850_B1-1G1; 유형 ID: 7667209; 패밀리 및 유형: BM111-철근콘크리트구조 보: BM110-철근 콘크리트구조 보_400 x 850_B1-1G1
기하학적 위치 - yz 맞춤: 균일; y 간격띄우기 값: 0 mm; y 맞춤: 원점; z 맞춤: 상단; 결합 상태: 두 결합 모두 사용
치수 - 단면적: 0.34 m2
Name (BM111-철근콘크리트구조 보:BM110-철근 콘크리트구조 보_400 x 850_B1-1G1:...) | In | CrossSectionArea (m2) | NetVolume (m3) = 체적 (m3) | Span (mm) = 길이 (mm) | 방향 | 참조 레벨 | 참조 레벨 입면도 (mm) | 작업 기준면 | 시작 부착 유형 | 절단 길이 (mm) | z 간격띄우기 값 (mm) | 상단 기준 레벨 (mm) | 하단 기준 레벨 (mm)
7667125 | 지상 1층 | 0.28 | 2.69472 | 10500 | 보통 | 지상 1층 | 0 | 레벨 : 지상 1층 | 끝 입면 | 9624 | 0 | 0 | -850
7667129 | 지상 1층 | 0.28 | 2.75487 | 9900 | 보통 | 지상 1층 | 0 | 레벨 : 지상 1층 |  | 9838.83 | 0 | 0 | -850
7667143 | 지상 1층 | 14.4395 | 2.27857 | 9107 |  | 지상 1층 | 0 |  |  | 9719.85 | -500 | -500 | -1350 | 구조 - 보강 철근 피복 - 상단 면: 보강 철근 피복 1 <25 mm>
7668163 | 지하1층 | 0.28 | 2.702 | 9725 | 보통 | 지하1층 | -6100 | 레벨 : 지하1층 | 끝 입면 | 9649.99 | 0 | -6100 | -6950
7668167 | 지하1층 | 0.28 | 2.772 | 10850 | 보통 | 지하1층 | -6100 | 레벨 : 지하1층 | 끝 입면 | 9900 | 0 | -6100 | -6950
7668168 | 지하1층 | 0.28 | 2.5476 | 9548 | 보통 | 지하1층 | -6100 | 레벨 : 지하1층 | 끝 입면 | 9098.57 | 0 | -6100 | -6950
7668184 | 지하1층 | 0.28 | 2.31 | 9150 | 보통 | 지하1층 | -6100 | 레벨 : 지하1층 | 끝 입면 | 8250.01 | 0 | -6100 | -6950 | 구조 - 보강 철근 피복 - 상단 면: 보강 철근 피복 1 <25 mm>
7668187 | 지하1층 | 0.28 | 2.548 | 9107 | 보통 | 지하1층 | -6100 | 레벨 : 지하1층 | 끝 입면 | 9100.01 | 0 | -6100 | -6950 | 구조 - 보강 철근 피복 - 상단 면: 보강 철근 피복 1 <25 mm>
7668217 | 지하1층 | 9.52224 | 2.2409 | 10000 | 보통 | 지하1층 | -6100 | 레벨 : 지하1층 | 끝 입면 | 9100 | 0 | -6100 | -6950 | 구조 - 보강 철근 피복 - 상단 면: 보강 철근 피복 1 <25 mm>
7668263 | 지상 1층 | 8.134 | 0.769297 | 10450 | 보통 | 지상 1층 | 0 | 레벨 : 지상 1층 | 끝 입면 | 9650 | 0 | 0 | -850
7668267 | 지상 1층 | 8.35359 | 0.801218 | 9900 | 보통 | 지상 1층 | 0 | 레벨 : 지상 1층 | 끝 입면 | 9898.57 | 0 | 0 | -850
7668268 | 지상 1층 | 7.70292 | 0.737742 | 9100 | 보통 | 지상 1층 | 0 | 레벨 : 지상 1층 | 끝 입면 | 9098.57 | 0 | 0 | -850
7668281 | 지상 1층 | 7.65202 | 0.733648 | 9107 |  | 지상 1층 | 0 |  | 끝 입면 | 9099.99 | -500 | -500 | -1350
7668310 | 지상 1층 | 0.28 | 2.548 | 10000 | 보통 | 지상 1층 | 0 | 레벨 : 지상 1층 | 끝 입면 | 9100.01 | -1500 | -1500 | -2350

# IfcBeam: BM111-철근콘크리트구조 보:BM110-철근 콘크리트구조 보_400 x 850_B1-1G2 (4)
Type - PredefinedType: BEAM; Material: KBIMS-콘크리트
Type - ID 데이터 - 유형 마크: G2; 유형 이름: BM110-철근 콘크리트구조 보_400 x 850_B1-1G2
Type - 구조 - 단면 모양: 0
Type - 기타 - 내화구조여부: yes; 주요구조부여부: yes; 카테고리: 구조 프레임; KBIMS-부위코드: E23; 제작정보: bSK-2021_KBIMS2.0-bC; 조달청표준공사코드: AD; 패밀리 이름: BM111-철근콘크리트구조 보
Type - 재료 및 마감재 - 구조 재료: KBIMS-콘크리트
Type - 치수 - 가로치수: 400 mm; 세로치수: 850 mm
Type - Pset_BeamCommon - IsExternal: no; LoadBearing: yes
Pset_BeamCommon - Slope: 0 deg; Reference: BM110-철근 콘크리트구조 보_400 x 850_B1-1G2
Pset_QuantityTakeOff - Reference: BM110-철근 콘크리트구조 보_400 x 850_B1-1G2; sets with these values: 2
ID 데이터 - 연관 있음: no
공정 - 생성 공정: 새 구성
구속조건 - 끝 레벨 간격띄우기: 0 mm; 단면형상 회전: 0 deg; 방향: 보통; 시작 레벨 간격띄우기: 0 mm
구조 - 보강 철근 피복 - 다른 면: 보강 철근 피복 1 <25 mm>; 보강 철근 피복 - 상단 면: 보강 철근 피복 1 <25 mm>; 보강 철근 피복 - 하단 면: 보강 철근 피복 1 <25 mm>; 시작 부착 유형: 끝 입면; 구조적 용도: 거더; 끝 부착 유형: 끝 입면
기타 - 패밀리: BM111-철근콘크리트구조 보; 유형: BM110-철근 콘크리트구조 보_400 x 850_B1-1G2; 유형 ID: 7667202; 패밀리 및 유형: BM111-철근콘크리트구조 보: BM110-철근 콘크리트구조 보_400 x 850_B1-1G2
기하학적 위치 - yz 맞춤: 균일; y 간격띄우기 값: 0 mm; y 맞춤: 원점; z 맞춤: 상단; 결합 상태: 두 결합 모두 사용
치수 - 단면적: 0.34 m2
Name (BM111-철근콘크리트구조 보:BM110-철근 콘크리트구조 보_400 x 850_B1-1G2:...) | In | Span (mm) = 길이 (mm) | Length (mm) | CrossSectionArea (m2) | OuterSurfaceArea (m2) | GrossSurfaceArea (m2) | GrossVolume (m3) | NetVolume (m3) = 체적 (m3) | NetSurfaceArea (m2) | 참조 레벨 | 참조 레벨 입면도 (mm) | 작업 기준면 | 절단 길이 (mm) | z 간격띄우기 값 (mm) | 상단 기준 레벨 (mm) | 하단 기준 레벨 (mm)
7667166 | 지상 1층 | 7600 | 1700 | 0.34 | 4.25 | 4.93 | 0.578 | 2.17595 | 17.3597 | 지상 1층 | 0 | 레벨 : 지상 1층 | 6599.86 | -400 | -400 | -1250
7667168 | 지상 1층 | 7800 | 5500 | 0.34 | 13.75 | 14.43 | 1.87 | 2.37971 | 18.8578 | 지상 1층 | 0 | 레벨 : 지상 1층 | 7199.14 | -450 | -450 | -1300
7668205 | 지하1층 | 7300 | 5010 | 0.26 | 10.521 | 11.041 | 1.3026 | 1.6146 | 14.081 | 지하1층 | -6100 | 레벨 : 지하1층 | 6300 | 0 | -6100 | -6950
7668304 | 지상 1층 | 7600 | 1700 | 0.0640045 | 3.14602 | 3.27403 | 0.108808 | 0.409629 | 12.0999 | 지상 1층 | 0 | 레벨 : 지상 1층 | 6600 | -400 | -400 | -1250

# IfcBeam: BM111-철근콘크리트구조 보:BM110-철근 콘크리트구조 보_400 x 850_B1-1G2 (29)
Type - PredefinedType: BEAM; Material: KBIMS-콘크리트 (2)
Type - ID 데이터 - 유형 마크: G2; 유형 이름: BM110-철근 콘크리트구조 보_400 x 850_B1-1G2
Type - 구조 - 단면 모양: 0
Type - 기타 - 내화구조여부: yes; 주요구조부여부: yes; 카테고리: 구조 프레임; KBIMS-부위코드: E23; 제작정보: bSK-2021_KBIMS2.0-bC; 조달청표준공사코드: AD; 패밀리 이름: BM111-철근콘크리트구조 보
Type - 재료 및 마감재 - 구조 재료: KBIMS-콘크리트
Type - 치수 - 가로치수: 400 mm; 세로치수: 850 mm
Type - Pset_BeamCommon - IsExternal: no; LoadBearing: yes
Pset_BeamCommon - Slope: 0 deg; Reference: BM110-철근 콘크리트구조 보_400 x 850_B1-1G2
Pset_QuantityTakeOff - Reference: BM110-철근 콘크리트구조 보_400 x 850_B1-1G2; sets with these values: 2
ID 데이터 - 연관 있음: no
공정 - 생성 공정: 새 구성
구속조건 - 끝 레벨 간격띄우기: 0 mm; 단면형상 회전: 0 deg; 시작 레벨 간격띄우기: 0 mm
구조 - 보강 철근 피복 - 다른 면: 보강 철근 피복 1 <25 mm>; 보강 철근 피복 - 하단 면: 보강 철근 피복 1 <25 mm>
기타 - 패밀리: BM111-철근콘크리트구조 보; 유형: BM110-철근 콘크리트구조 보_400 x 850_B1-1G2; 유형 ID: 7667202; 패밀리 및 유형: BM111-철근콘크리트구조 보: BM110-철근 콘크리트구조 보_400 x 850_B1-1G2
기하학적 위치 - yz 맞춤: 균일; y 간격띄우기 값: 0 mm; y 맞춤: 원점; z 맞춤: 상단; 결합 상태: 두 결합 모두 사용
치수 - 단면적: 0.34 m2
Name (BM111-철근콘크리트구조 보:BM110-철근 콘크리트구조 보_400 x 850_B1-1G2:...) | In | Span (mm) = 길이 (mm) | CrossSectionArea (m2) | NetVolume (m3) = 체적 (m3) | 방향 | 참조 레벨 | 참조 레벨 입면도 (mm) | 작업 기준면 | 구조적 용도 | 시작 부착 유형 | 끝 부착 유형 | 절단 길이 (mm) | z 간격띄우기 값 (mm) | 상단 기준 레벨 (mm) | 하단 기준 레벨 (mm) | Material
7667141 | 지상 1층 | 9200 | 9.86959 | 2.3519 | 보통 | 지상 1층 | 0 | 레벨 : 지상 1층 | 기타 | 끝 입면 | 끝 입면 | 9399.63 | 0 | 0 | -850 | BaseQuantities - NetSurfaceArea: 19.7392 m2; 구조 - 보강 철근 피복 - 상단 면: 보강 철근 피복 1 <25 mm>
7667147 | 지상 1층 | 8500 | 0.28 | 2.18008 |  | 지상 1층 | 0 |  | 거더 | 끝 입면 | 끝 입면 | 7786 | 0 | 0 | -850 | KBIMS-콘크리트
7667148 | 지상 1층 | 8482 | 9.25083 | 2.25359 |  | 지상 1층 | 0 |  | 거더 | 끝 입면 |  | 8581.69 | 0 | 0 | -850 | BaseQuantities - NetSurfaceArea: 18.5017 m2
7667151 | 지상 1층 | 8450 | 9.07795 | 2.16507 |  | 지상 1층 | 0 |  | 거더 | 끝 입면 | 끝 입면 | 8150 | 0 | 0 | -850 | KBIMS-콘크리트 | 구조 - 보강 철근 피복 - 상단 면: 보강 철근 피복 1 <25 mm>
7667152 | 지상 1층 | 8450 | 0.28 | 2.13812 | 보통 | 지상 1층 | 0 | 레벨 : 지상 1층 | 거더 | 끝 입면 | 끝 입면 | 7636.14 | 0 | 0 | -850 | KBIMS-콘크리트
7667155 | 지상 1층 | 8650 | 0.28 | 2.13808 | 보통 | 지상 1층 | 0 | 레벨 : 지상 1층 | 거더 | 끝 입면 | 끝 입면 | 7636 | 0 | 0 | -850 | KBIMS-콘크리트 | 구조 - 보강 철근 피복 - 상단 면: 보강 철근 피복 1 <25 mm>
7667158 | 지상 1층 | 8650 | 9.40342 | 2.17762 | 보통 | 지상 1층 | 0 | 레벨 : 지상 1층 | 거더 | 끝 입면 | 끝 입면 | 8400 | 0 | 0 | -850 | KBIMS-콘크리트 | 구조 - 보강 철근 피복 - 상단 면: 보강 철근 피복 1 <25 mm>
7667159 | 지상 1층 | 7300 | 0.34 | 2.20971 | 보통 | 지상 1층 | 0 | 레벨 : 지상 1층 | 거더 | 끝 입면 | 끝 입면 | 6499.14 | -400 | -400 | -1250 | KBIMS-콘크리트 | 구조 - 보강 철근 피복 - 상단 면: 보강 철근 피복 1 <25 mm>
7667174 | 지상 1층 | 8229 | 8.40121 | 2.00259 | 보통 | 지상 1층 | 0 | 레벨 : 지상 1층 | 기타 | 끝 입면 | 끝 입면 | 7726.63 | 0 | 0 | -850 | BaseQuantities - NetSurfaceArea: 16.8024 m2; 구조 - 보강 철근 피복 - 상단 면: 보강 철근 피복 1 <25 mm>
7668186 | 지하1층 | 4907 | 0.26 | 1.248 | 보통 | 지하1층 | -6100 | 레벨 : 지하1층 | 기타 | 끝 입면 |  | 4799.98 | 0 | -6100 | -6950 | KBIMS-콘크리트
7668193 | 지하1층 | 8450 | 0.28 | 2.198 | 보통 | 지하1층 | -6100 | 레벨 : 지하1층 | 거더 | 끝 입면 | 끝 입면 | 7850 | 0 | -6100 | -6950 | KBIMS-콘크리트
7668194 | 지하1층 | 8665 | 0.28 | 2.28357 | 보통 | 지하1층 | -6100 | 레벨 : 지하1층 | 거더 | 끝 입면 | 끝 입면 | 8220.59 | 0 | -6100 | -6950 | KBIMS-콘크리트
7668197 | 지하1층 | 8400 | 0.28 | 2.17 | 보통 | 지하1층 | -6100 | 레벨 : 지하1층 | 거더 | 끝 입면 | 끝 입면 | 7750 | 0 | -6100 | -6950 | KBIMS-콘크리트 | 구조 - 보강 철근 피복 - 상단 면: 보강 철근 피복 1 <25 mm>
7668198 | 지하1층 | 8400 | 0.28 | 2.17 | 보통 | 지하1층 | -6100 | 레벨 : 지하1층 | 거더 | 끝 입면 | 끝 입면 | 7750 | 0 | -6100 | -6950 | KBIMS-콘크리트 | 구조 - 보강 철근 피복 - 상단 면: 보강 철근 피복 1 <25 mm>
7668201 | 지하1층 | 8400 | 0.28 | 2.17 | 보통 | 지하1층 | -6100 | 레벨 : 지하1층 | 거더 | 끝 입면 | 끝 입면 | 7750 | 0 | -6100 | -6950 | KBIMS-콘크리트
7668204 | 지하1층 | 8450 | 0.28 | 2.198 | 보통 | 지하1층 | -6100 | 레벨 : 지하1층 | 거더 | 끝 입면 | 끝 입면 | 7850 | 0 | -6100 | -6950 | KBIMS-콘크리트 | 구조 - 보강 철근 피복 - 상단 면: 보강 철근 피복 1 <25 mm>
7668211 | 지하1층 | 7600 | 0.26 | 1.716 | 보통 | 지하1층 | -6100 | 레벨 : 지하1층 | 거더 | 끝 입면 | 끝 입면 | 6600 | 0 | -6100 | -6950 | KBIMS-콘크리트
7668279 | 지상 1층 | 9050 | 0.0797051 | 0.655552 | 보통 | 지상 1층 | 0 | 레벨 : 지상 1층 | 기타 | 끝 입면 | 끝 입면 | 8224.71 | 0 | 0 | -850 | KBIMS-콘크리트
7668285 | 지상 1층 | 8500 | 0.0527066 | 0.410339 |  | 지상 1층 | 0 |  | 거더 | 끝 입면 | 끝 입면 | 7785.64 | 0 | 0 | -850 | KBIMS-콘크리트
7668286 | 지상 1층 | 8481 | 0.0392428 | 0.317509 |  | 지상 1층 | 0 |  | 거더 | 끝 입면 | 끝 입면 | 8100 | 0 | 0 | -850 | KBIMS-콘크리트
7668289 | 지상 1층 | 8450 | 0.0527096 | 0.402498 |  | 지상 1층 | 0 |  | 거더 | 끝 입면 | 끝 입면 | 7636.14 | 0 | 0 | -850 | KBIMS-콘크리트
7668290 | 지상 1층 | 8450 | 0.0527066 | 0.405102 | 보통 | 지상 1층 | 0 | 레벨 : 지상 1층 | 거더 | 끝 입면 | 끝 입면 | 7686.14 | 0 | 0 | -850 | KBIMS-콘크리트
7668293 | 지상 1층 | 8450 | 0.0527096 | 0.402498 | 보통 | 지상 1층 | 0 | 레벨 : 지상 1층 | 거더 | 끝 입면 | 끝 입면 | 7636.14 | 0 | 0 | -850 | KBIMS-콘크리트
7668296 | 지상 1층 | 8450 | 0.0527096 | 0.407769 | 보통 | 지상 1층 | 0 | 레벨 : 지상 1층 | 거더 | 끝 입면 | 끝 입면 | 7736.14 | 0 | 0 | -850 | KBIMS-콘크리트
7668297 | 지상 1층 | 7300 | 6.20861 | 0.416142 | 보통 | 지상 1층 | 0 | 레벨 : 지상 1층 | 거더 | 끝 입면 | 끝 입면 | 6500 | -400 | -400 | -1250 | KBIMS-콘크리트 | 구조 - 보강 철근 피복 - 상단 면: 보강 철근 피복 1 <25 mm>
7668311 | 지상 1층 | 6299 | 0.26 | 1.534 | 보통 | 지상 1층 | 0 | 레벨 : 지상 1층 | 거더 | 끝 입면 | 끝 입면 | 5900 | -2100 | -2100 | -2950 | KBIMS-콘크리트
7668312 | 지상 1층 | 7800 | 0.0640045 | 0.448021 | 보통 | 지상 1층 | 0 | 레벨 : 지상 1층 | 거더 | 끝 입면 | 끝 입면 | 7199 | -450 | -450 | -1300 | BaseQuantities - NetSurfaceArea: 13.5008 m2; Length: 5499.5 mm; OuterSurfaceArea: 10.1774 m2; GrossSurfaceArea: 10.3054 m2; GrossVolume: 0.351993 m3; 구조 - 보강 철근 피복 - 상단 면: 보강 철근 피복 1 <25 mm>
7668318 | 지상 1층 | 8690 | 6.02368 | 0.574797 | 보통 | 지상 1층 | 0 | 레벨 : 지상 1층 | 기타 | 끝 입면 | 끝 입면 | 7480.01 | 0 | 0 | -850 | BaseQuantities - NetSurfaceArea: 12.0474 m2
7668320 | 지상 1층 | 7600 | 5.28452 | 0.352067 | 보통 | 지상 1층 | 0 | 레벨 : 지상 1층 | 거더 |  | 끝 입면 | 7286.14 | 0 | 0 | -850 | BaseQuantities - NetSurfaceArea: 10.569 m2

# IfcBeam: BM111-철근콘크리트구조 보:BM110-철근 콘크리트구조 보_400 x 850_B1-1G2, BM111-철근콘크리트구조 보:BM110-철근 콘크리트구조 보_400 x 850_B1-1G2:7667176
In: 지상 1층
Type - PredefinedType: BEAM; Material: KBIMS-콘크리트 (3)
Type - ID 데이터 - 유형 마크: G2; 유형 이름: BM110-철근 콘크리트구조 보_400 x 850_B1-1G2
Type - 구조 - 단면 모양: 0
Type - 기타 - 내화구조여부: yes; 주요구조부여부: yes; 카테고리: 구조 프레임; KBIMS-부위코드: E23; 제작정보: bSK-2021_KBIMS2.0-bC; 조달청표준공사코드: AD; 패밀리 이름: BM111-철근콘크리트구조 보
Type - 재료 및 마감재 - 구조 재료: KBIMS-콘크리트
Type - 치수 - 가로치수: 400 mm; 세로치수: 850 mm
Type - Pset_BeamCommon - IsExternal: no; LoadBearing: yes
Pset_BeamCommon - Slope: 0 deg; Reference: BM110-철근 콘크리트구조 보_400 x 850_B1-1G2; Span: 7600 mm
Pset_QuantityTakeOff - Reference: BM110-철근 콘크리트구조 보_400 x 850_B1-1G2; sets with these values: 2
BaseQuantities - CrossSectionArea: 12.1111 m2; NetVolume: 1.04857 m3; NetSurfaceArea: 24.2222 m2
ID 데이터 - 연관 있음: no
공정 - 생성 공정: 새 구성
구속조건 - 끝 레벨 간격띄우기: 0 mm; 단면형상 회전: 0 deg; 방향: 보통; 시작 레벨 간격띄우기: 0 mm; 참조 레벨: 지상 1층; 참조 레벨 입면도: 0 mm; 작업 기준면: 레벨 : 지상 1층
구조 - 보강 철근 피복 - 다른 면: 보강 철근 피복 1 <25 mm>; 보강 철근 피복 - 상단 면: 보강 철근 피복 1 <25 mm>; 보강 철근 피복 - 하단 면: 보강 철근 피복 1 <25 mm>; 구조적 용도: 거더; 끝 부착 유형: 끝 입면; 절단 길이: 7486 mm
기타 - 패밀리: BM111-철근콘크리트구조 보; 유형: BM110-철근 콘크리트구조 보_400 x 850_B1-1G2; 유형 ID: 7667202; 패밀리 및 유형: BM111-철근콘크리트구조 보: BM110-철근 콘크리트구조 보_400 x 850_B1-1G2
기하학적 위치 - yz 맞춤: 균일; y 간격띄우기 값: 0 mm; y 맞춤: 원점; z 간격띄우기 값: 0 mm; z 맞춤: 상단; 결합 상태: 두 결합 모두 사용
치수 - 상단 기준 레벨: 0 mm; 길이: 7600 mm; 단면적: 0.34 m2; 체적: 1.04857 m3; 하단 기준 레벨: -850 mm

# IfcBeam: BM111-철근콘크리트구조 보:BM110-철근 콘크리트구조 보_400 x 850_B1-1G3, BM111-철근콘크리트구조 보:BM110-철근 콘크리트구조 보_400 x 850_B1-1G3:7667122
In: 지상 1층
Type - PredefinedType: BEAM; Material: KBIMS-콘크리트
Type - ID 데이터 - 유형 마크: G3; 유형 이름: BM110-철근 콘크리트구조 보_400 x 850_B1-1G3
Type - 구조 - 단면 모양: 0
Type - 기타 - 내화구조여부: yes; 주요구조부여부: yes; 카테고리: 구조 프레임; KBIMS-부위코드: E23; 제작정보: bSK-2021_KBIMS2.0-bC; 조달청표준공사코드: AD; 패밀리 이름: BM111-철근콘크리트구조 보
Type - 재료 및 마감재 - 구조 재료: KBIMS-콘크리트
Type - 치수 - 가로치수: 400 mm; 세로치수: 850 mm
Type - Pset_BeamCommon - IsExternal: no; LoadBearing: yes
Pset_BeamCommon - Reference: BM110-철근 콘크리트구조 보_400 x 850_B1-1G3; Slope: 0 deg; Span: 2600 mm
Pset_QuantityTakeOff - Reference: BM110-철근 콘크리트구조 보_400 x 850_B1-1G3; sets with these values: 2
BaseQuantities - Length: 63.8645 mm; CrossSectionArea: 0.28 m2; OuterSurfaceArea: 0.140502 m2; GrossSurfaceArea: 0.700502 m2; GrossVolume: 0.0178821 m3; NetVolume: 0.703556 m3; NetSurfaceArea: 6.64794 m2
ID 데이터 - 연관 있음: no
공정 - 생성 공정: 새 구성
구속조건 - 끝 레벨 간격띄우기: 0 mm; 단면형상 회전: 0 deg; 시작 레벨 간격띄우기: 0 mm; 참조 레벨: 지상 1층; 참조 레벨 입면도: 0 mm
구조 - 보강 철근 피복 - 다른 면: 보강 철근 피복 1 <25 mm>; 보강 철근 피복 - 하단 면: 보강 철근 피복 1 <25 mm>; 구조적 용도: 거더; 끝 부착 유형: 끝 입면; 절단 길이: 3012.7 mm
기타 - 유형: BM110-철근 콘크리트구조 보_400 x 850_B1-1G3; 유형 ID: 7667203; 패밀리: BM111-철근콘크리트구조 보; 패밀리 및 유형: BM111-철근콘크리트구조 보: BM110-철근 콘크리트구조 보_400 x 850_B1-1G3
기하학적 위치 - yz 맞춤: 균일; y 간격띄우기 값: 0 mm; y 맞춤: 원점; z 간격띄우기 값: 0 mm; z 맞춤: 상단; 결합 상태: 두 결합 모두 사용
치수 - 상단 기준 레벨: 0 mm; 길이: 2600 mm; 단면적: 0.34 m2; 체적: 0.703556 m3; 하단 기준 레벨: -850 mm

# IfcBeam: BM111-철근콘크리트구조 보:BM110-철근 콘크리트구조 보_400 x 850_B1-1G3 (66)
Type - ID 데이터 - 유형 마크: G3; 유형 이름: BM110-철근 콘크리트구조 보_400 x 850_B1-1G3
Type - 구조 - 단면 모양: 0
Type - 기타 - 내화구조여부: yes; 주요구조부여부: yes; 카테고리: 구조 프레임; KBIMS-부위코드: E23; 제작정보: bSK-2021_KBIMS2.0-bC; 조달청표준공사코드: AD; 패밀리 이름: BM111-철근콘크리트구조 보
Type - 재료 및 마감재 - 구조 재료: KBIMS-콘크리트
Type - 치수 - 가로치수: 400 mm; 세로치수: 850 mm
Type - Pset_BeamCommon - IsExternal: no; LoadBearing: yes
Material: KBIMS-콘크리트
Pset_BeamCommon - Reference: BM110-철근 콘크리트구조 보_400 x 850_B1-1G3; Slope: 0 deg
Pset_QuantityTakeOff - Reference: BM110-철근 콘크리트구조 보_400 x 850_B1-1G3; sets with these values: 2
ID 데이터 - 연관 있음: no
공정 - 생성 공정: 새 구성
구속조건 - 끝 레벨 간격띄우기: 0 mm; 단면형상 회전: 0 deg; 시작 레벨 간격띄우기: 0 mm
구조 - 보강 철근 피복 - 다른 면: 보강 철근 피복 1 <25 mm>; 보강 철근 피복 - 하단 면: 보강 철근 피복 1 <25 mm>
기타 - 유형: BM110-철근 콘크리트구조 보_400 x 850_B1-1G3; 유형 ID: 7667203; 패밀리: BM111-철근콘크리트구조 보; 패밀리 및 유형: BM111-철근콘크리트구조 보: BM110-철근 콘크리트구조 보_400 x 850_B1-1G3
기하학적 위치 - yz 맞춤: 균일; y 간격띄우기 값: 0 mm; y 맞춤: 원점; z 간격띄우기 값: 0 mm; z 맞춤: 상단; 결합 상태: 두 결합 모두 사용
치수 - 단면적: 0.34 m2
Name (BM111-철근콘크리트구조 보:BM110-철근 콘크리트구조 보_400 x 850_B1-1G3:...) | In | CrossSectionArea (m2) | NetVolume (m3) = 체적 (m3) | Span (mm) = 길이 (mm) | 방향 | 작업 기준면 | 참조 레벨 | 참조 레벨 입면도 (mm) = 상단 기준 레벨 (mm) | 구조적 용도 | 시작 부착 유형 | 절단 길이 (mm) | 하단 기준 레벨 (mm) | 끝 부착 유형
7667121 | 지상 1층 | 2.79119 | 0.484406 | 1900 | 보통 | 레벨 : 지상 1층 | 지상 1층 | 0 | 기타 | 끝 입면 | 2212.69 | -850
7667123 | 지상 1층 | 2.64958 | 0.580704 | 2349 |  |  | 지상 1층 | 0 | 기타 | 끝 입면 | 2200.01 | -850 | 끝 입면 | 구조 - 보강 철근 피복 - 상단 면: 보강 철근 피복 1 <25 mm>
7667124 | 지상 1층 | 3.48234 | 0.796134 | 3437 |  |  | 지상 1층 | 0 | 거더 | 끝 입면 | 2950 | -850 | 끝 입면
7667126 | 지상 1층 | 3.67275 | 0.733428 | 2950 | 보통 | 레벨 : 지상 1층 | 지상 1층 | 0 | 거더 | 끝 입면 | 3350 | -850 | 끝 입면 | 구조 - 보강 철근 피복 - 상단 면: 보강 철근 피복 1 <25 mm>
7667127 | 지상 1층 | 0.28 | 0.678921 | 3250 | 보통 | 레벨 : 지상 1층 | 지상 1층 | 0 | 기타 | 끝 입면 | 2424.72 | -850 | 끝 입면
7667128 | 지상 1층 | 0.28 | 0.686 | 3150 | 보통 | 레벨 : 지상 1층 | 지상 1층 | 0 | 거더 | 끝 입면 | 2450 | -850 | 끝 입면
7667132 | 지상 1층 | 3.0047 | 0.682287 | 2850 | 보통 | 레벨 : 지상 1층 | 지상 1층 | 0 | 기타 | 끝 입면 | 2500 | -850 | 끝 입면 | 구조 - 보강 철근 피복 - 상단 면: 보강 철근 피복 1 <25 mm>
7667135 | 지상 1층 | 4.35194 | 0.877979 | 3649 | 보통 | 레벨 : 지상 1층 | 지상 1층 | 0 | 기타 | 끝 입면 | 3992.25 | -850 | 끝 입면 | 구조 - 보강 철근 피복 - 상단 면: 보강 철근 피복 1 <25 mm>
7667137 | 지상 1층 | 3.4565 | 0.728862 | 3050 | 보통 | 레벨 : 지상 1층 | 지상 1층 | 0 | 기타 |  | 3050.38 | -850 | 끝 입면 | 구조 - 보강 철근 피복 - 상단 면: 보강 철근 피복 1 <25 mm>
7667140 | 지상 1층 | 3.82227 | 0.874697 | 3649 | 보통 | 레벨 : 지상 1층 | 지상 1층 | 0 | 기타 | 끝 입면 | 3275.29 | -850 | 끝 입면
7667142 | 지상 1층 | 0.28 | 0.67851 | 2723 | 보통 | 레벨 : 지상 1층 | 지상 1층 | 0 | 기타 | 끝 입면 | 2423.25 | -850 | 구조 - 보강 철근 피복 - 상단 면: 보강 철근 피복 1 <25 mm>
7667144 | 지상 1층 | 5.11264 | 0.996672 | 4304 | 보통 | 레벨 : 지상 1층 | 지상 1층 | 0 | 기타 | 끝 입면 | 4797.62 | -850 | 끝 입면 | 구조 - 보강 철근 피복 - 상단 면: 보강 철근 피복 1 <25 mm>
7667145 | 지상 1층 | 0.28 | 0.686 | 3150 | 보통 | 레벨 : 지상 1층 | 지상 1층 | 0 | 거더 | 끝 입면 | 2450 | -850 | 끝 입면 | 구조 - 보강 철근 피복 - 상단 면: 보강 철근 피복 1 <25 mm>
7667146 | 지상 1층 | 3.05199 | 0.681888 | 2799 | 보통 | 레벨 : 지상 1층 | 지상 1층 | 0 | 거더 |  | 2562.2 | -850 | 끝 입면
7667175 | 지상 1층 | 2.92617 | 0.669521 | 3040 | 보통 | 레벨 : 지상 1층 | 지상 1층 | 0 | 기타 | 끝 입면 | 2498.14 | -850 | 구조 - 보강 철근 피복 - 상단 면: 보강 철근 피복 1 <25 mm>
7667191 | 지상 1층 | 1.50704 | 0.292 | 1914 | 보통 | 레벨 : 지상 1층 | 지상 1층 | 0 | 거더 | 끝 입면 | 1213.86 | -850
7667192 | 지상 1층 | 0.26 | 0.286 | 2776 | 보통 | 레벨 : 지상 1층 | 지상 1층 | 0 | 거더 |  | 1100 | -850
7667193 | 지상 1층 | 0.26 | 0.285761 | 1531 | 보통 | 레벨 : 지상 1층 | 지상 1층 | 0 | 거더 | 끝 입면 | 1099.08 | -850
7667195 | 지상 1층 | 0.26 | 0.935995 | 3925 | 보통 | 레벨 : 지상 1층 | 지상 1층 | 0 | 기타 |  | 3599.98 | -850 | 끝 입면
7667196 | 지상 1층 | 3.93385 | 0.89706 | 3920 | 보통 | 레벨 : 지상 1층 | 지상 1층 | 0 | 기타 | 끝 입면 | 3562.57 | -850
7668157 | 지하1층 | 4.45148 | 1.0686 | 3850 | 보통 | 레벨 : 지하1층 | 지하1층 | -6100 | 기타 |  | 3599.98 | -6950 | 끝 입면 | 구조 - 보강 철근 피복 - 상단 면: 보강 철근 피복 1 <25 mm>
7668158 | 지하1층 | 0.28 | 0.489998 | 1900 | 보통 | 레벨 : 지하1층 | 지하1층 | -6100 | 기타 | 끝 입면 | 1749.99 | -6950 | 끝 입면
7668159 | 지하1층 | 0.28 | 0.714 | 2600 | 보통 | 레벨 : 지하1층 | 지하1층 | -6100 | 거더 | 끝 입면 | 2550 | -6950 | 끝 입면
7668160 | 지하1층 | 0.28 | 0.96691 | 3961 | 보통 | 레벨 : 지하1층 | 지하1층 | -6100 | 기타 | 끝 입면 | 3503.25 | -6950 | 구조 - 보강 철근 피복 - 상단 면: 보강 철근 피복 1 <25 mm>
7668161 | 지하1층 | 0.28 | 0.573998 | 2450 | 보통 | 레벨 : 지하1층 | 지하1층 | -6100 | 기타 | 끝 입면 | 2049.99 | -6950 | 끝 입면 | 구조 - 보강 철근 피복 - 상단 면: 보강 철근 피복 1 <25 mm>
7668162 | 지하1층 | 0.28 | 0.798 | 3283 | 보통 | 레벨 : 지하1층 | 지하1층 | -6100 | 거더 | 끝 입면 | 2850 | -6950 | 끝 입면
7668164 | 지하1층 | 0.28 | 0.686 | 3200 | 보통 | 레벨 : 지하1층 | 지하1층 | -6100 | 거더 | 끝 입면 | 2450 | -6950 | 끝 입면
7668165 | 지하1층 | 0.28 | 0.7 | 2900 | 보통 | 레벨 : 지하1층 | 지하1층 | -6100 | 기타 | 끝 입면 | 2500 | -6950 | 끝 입면
7668166 | 지하1층 | 0.28 | 0.686 | 3200 | 보통 | 레벨 : 지하1층 | 지하1층 | -6100 | 거더 | 끝 입면 | 2450 | -6950 | 끝 입면
7668169 | 지하1층 | 0.28 | 0.308002 | 1750 | 보통 | 레벨 : 지하1층 | 지하1층 | -6100 | 기타 |  | 1100.01 | -6950 | 끝 입면
7668171 | 지하1층 | 0.291138 | 0.727845 | 3300 | 보통 | 레벨 : 지하1층 | 지하1층 | -6100 | 기타 | 끝 입면 | 2500 | -6950 | 끝 입면 | 구조 - 보강 철근 피복 - 상단 면: 보강 철근 피복 1 <25 mm>
7668174 | 지하1층 | 0.268787 | 0.360623 | 1999 | 보통 | 레벨 : 지하1층 | 지하1층 | -6100 | 기타 | 끝 입면 | 1390.75 | -6950
7668175 | 지하1층 | 0.28 | 0.308002 | 1700 | 보통 | 레벨 : 지하1층 | 지하1층 | -6100 | 기타 |  | 1100.01 | -6950 | 끝 입면
7668176 | 지하1층 | 0.273638 | 0.793548 | 3650 | 보통 | 레벨 : 지하1층 | 지하1층 | -6100 | 기타 | 끝 입면 | 2899.99 | -6950 | 끝 입면 | 구조 - 보강 철근 피복 - 상단 면: 보강 철근 피복 1 <25 mm>
7668178 | 지하1층 | 0.28 | 0.7 | 3050 | 보통 | 레벨 : 지하1층 | 지하1층 | -6100 | 기타 | 끝 입면 | 2500 | -6950 | 끝 입면 | 구조 - 보강 철근 피복 - 상단 면: 보강 철근 피복 1 <25 mm>
7668181 | 지하1층 | 0.28 | 0.308002 | 1750 | 보통 | 레벨 : 지하1층 | 지하1층 | -6100 | 기타 | 끝 입면 | 1100.01 | -6950
7668182 | 지하1층 | 0.26 | 0.155995 | 1250 | 보통 | 레벨 : 지하1층 | 지하1층 | -6100 | 기타 | 끝 입면 | 599.983 | -6950 | 구조 - 보강 철근 피복 - 상단 면: 보강 철근 피복 1 <25 mm>
7668183 | 지하1층 | 0.26 | 0.766998 | 3650 | 보통 | 레벨 : 지하1층 | 지하1층 | -6100 | 기타 | 끝 입면 | 2949.99 | -6950 | 끝 입면
7668185 | 지하1층 | 0.28 | 0.644002 | 2948 | 보통 | 레벨 : 지하1층 | 지하1층 | -6100 | 기타 | 끝 입면 | 2300.01 | -6950
7668188 | 지하1층 | 0.28 | 0.308005 | 1350 | 보통 | 레벨 : 지하1층 | 지하1층 | -6100 | 기타 | 끝 입면 | 1100.02 | -6950
7668189 | 지하1층 | 0.13 | 0.0779976 | 1250 | 보통 | 레벨 : 지하1층 | 지하1층 | -6100 | 기타 | 끝 입면 | 599.983 | -6950
7668190 | 지하1층 | 0.13 | 0.415998 | 4143 | 보통 | 레벨 : 지하1층 | 지하1층 | -6100 | 기타 | 끝 입면 | 3199.99 | -6950 | 끝 입면
7668191 | 지하1층 | 0.28 | 0.686 | 3200 | 보통 | 레벨 : 지하1층 | 지하1층 | -6100 | 거더 | 끝 입면 | 2450 | -6950 | 끝 입면
7668192 | 지하1층 | 0.28 | 0.714 | 2850 | 보통 | 레벨 : 지하1층 | 지하1층 | -6100 | 거더 | 끝 입면 | 2550 | -6950 | 끝 입면
7668222 | 지하1층 | 0.28 | 0.308005 | 1350 | 보통 | 레벨 : 지하1층 | 지하1층 | -6100 | 기타 | 끝 입면 | 1100.02 | -6950
7668259 | 지상 1층 | 1.72217 | 0.152022 | 1900 | 보통 | 레벨 : 지상 1층 | 지상 1층 | 0 | 기타 | 끝 입면 | 1749.99 | -850 | 끝 입면
7668260 | 지상 1층 | 2.28986 | 0.157403 | 2600 |  |  | 지상 1층 | 0 | 거더 | 끝 입면 | 2550 | -850 | 끝 입면
7668261 | 지상 1층 | 0.0797051 | 0.163395 | 2350 |  |  | 지상 1층 | 0 | 기타 | 끝 입면 | 2049.99 | -850 | 끝 입면
7668262 | 지상 1층 | 0.0527096 | 0.149492 | 3438 |  |  | 지상 1층 | 0 | 거더 | 끝 입면 | 2836.14 | -850 | 끝 입면
7668264 | 지상 1층 | 0.0527096 | 0.129139 | 2950 | 보통 | 레벨 : 지상 1층 | 지상 1층 | 0 | 거더 | 끝 입면 | 2450 | -850 | 끝 입면
7668265 | 지상 1층 | 0.0797051 | 0.193263 | 3050 | 보통 | 레벨 : 지상 1층 | 지상 1층 | 0 | 기타 | 끝 입면 | 2424.72 | -850 | 끝 입면
7668266 | 지상 1층 | 0.0527096 | 0.129139 | 2950 | 보통 | 레벨 : 지상 1층 | 지상 1층 | 0 | 거더 | 끝 입면 | 2450 | -850 | 끝 입면
7668270 | 지상 1층 | 0.0797051 | 0.193261 | 2800 | 보통 | 레벨 : 지상 1층 | 지상 1층 | 0 | 기타 | 끝 입면 | 2424.7 | -850 | 끝 입면
7668273 | 지상 1층 | 0.0797051 | 0.231144 | 3650 | 보통 | 레벨 : 지상 1층 | 지상 1층 | 0 | 기타 | 끝 입면 | 2899.99 | -850 | 끝 입면
7668275 | 지상 1층 | 0.0797051 | 0.193291 | 3050 | 보통 | 레벨 : 지상 1층 | 지상 1층 | 0 | 기타 | 끝 입면 | 2425.08 | -850 | 끝 입면
7668278 | 지상 1층 | 0.0797051 | 0.235129 | 3650 | 보통 | 레벨 : 지상 1층 | 지상 1층 | 0 | 기타 | 끝 입면 | 2949.99 | -850 | 끝 입면
7668280 | 지상 1층 | 1.95189 | 0.183351 | 2948 | 보통 | 레벨 : 지상 1층 | 지상 1층 | 0 | 기타 | 끝 입면 | 2300.37 | -850
7668282 | 지상 1층 | 0.0797051 | 0.255056 | 4160 | 보통 | 레벨 : 지상 1층 | 지상 1층 | 0 | 기타 | 끝 입면 | 3199.99 | -850 | 끝 입면
7668283 | 지상 1층 | 0.0527096 | 0.129139 | 2950 | 보통 | 레벨 : 지상 1층 | 지상 1층 | 0 | 거더 | 끝 입면 | 2450 | -850 | 끝 입면
7668284 | 지상 1층 | 2.29002 | 0.157517 | 2600 | 보통 | 레벨 : 지상 1층 | 지상 1층 | 0 | 거더 | 끝 입면 | 2550 | -850 | 끝 입면
7668319 | 지상 1층 | 0.0797051 | 0.183169 | 2948 | 보통 | 레벨 : 지상 1층 | 지상 1층 | 0 | 기타 | 끝 입면 | 2298.08 | -850
7669268 | 지상 1층 | 0.0489446 | 0.0538391 | 1800 | 보통 | 레벨 : 지상 1층 | 지상 1층 | 0 | 거더 | 끝 입면 | 1100 | -850
7669269 | 지상 1층 | 0.0489446 | 0.0538391 | 2662 | 보통 | 레벨 : 지상 1층 | 지상 1층 | 0 | 거더 |  | 1100 | -850
7669270 | 지상 1층 | 1.05813 | 0.0540329 | 1417 | 보통 | 레벨 : 지상 1층 | 지상 1층 | 0 | 거더 | 끝 입면 | 1100 | -850
7669272 | 지상 1층 | 0.0740119 | 0.266442 | 3850 | 보통 | 레벨 : 지상 1층 | 지상 1층 | 0 | 기타 |  | 3599.98 | -850 | 끝 입면
7669273 | 지상 1층 | 0.0740119 | 0.259154 | 3874 | 보통 | 레벨 : 지상 1층 | 지상 1층 | 0 | 기타 | 끝 입면 | 3515.75 | -850

# IfcBeam: BM111-철근콘크리트구조 보:BM110-철근 콘크리트구조 보_400 x 850_B1-1G4 (8)
Type - PredefinedType: BEAM; Material: KBIMS-콘크리트
Type - ID 데이터 - 유형 마크: G4; 유형 이름: BM110-철근 콘크리트구조 보_400 x 850_B1-1G4
Type - 구조 - 단면 모양: 0
Type - 기타 - 내화구조여부: yes; 주요구조부여부: yes; 카테고리: 구조 프레임; KBIMS-부위코드: E23; 제작정보: bSK-2021_KBIMS2.0-bC; 조달청표준공사코드: AD; 패밀리 이름: BM111-철근콘크리트구조 보
Type - 재료 및 마감재 - 구조 재료: KBIMS-콘크리트
Type - 치수 - 가로치수: 400 mm; 세로치수: 850 mm
Type - Pset_BeamCommon - IsExternal: no; LoadBearing: yes
Pset_BeamCommon - Slope: 0 deg; Reference: BM110-철근 콘크리트구조 보_400 x 850_B1-1G4
Pset_QuantityTakeOff - Reference: BM110-철근 콘크리트구조 보_400 x 850_B1-1G4; sets with these values: 2
ID 데이터 - 연관 있음: no
공정 - 생성 공정: 새 구성
구속조건 - 끝 레벨 간격띄우기: 0 mm; 단면형상 회전: 0 deg; 방향: 보통; 시작 레벨 간격띄우기: 0 mm
구조 - 보강 철근 피복 - 다른 면: 보강 철근 피복 1 <25 mm>; 보강 철근 피복 - 하단 면: 보강 철근 피복 1 <25 mm>; 시작 부착 유형: 끝 입면; 구조적 용도: 거더; 끝 부착 유형: 끝 입면
기타 - 패밀리: BM111-철근콘크리트구조 보; 유형: BM110-철근 콘크리트구조 보_400 x 850_B1-1G4; 유형 ID: 7667204; 패밀리 및 유형: BM111-철근콘크리트구조 보: BM110-철근 콘크리트구조 보_400 x 850_B1-1G4
기하학적 위치 - yz 맞춤: 균일; y 간격띄우기 값: 0 mm; y 맞춤: 원점; z 맞춤: 상단; 결합 상태: 두 결합 모두 사용
치수 - 단면적: 0.34 m2
Name (BM111-철근콘크리트구조 보:BM110-철근 콘크리트구조 보_400 x 850_B1-1G4:...) | In | Span (mm) = 길이 (mm) | Length (mm) | CrossSectionArea (m2) | OuterSurfaceArea (m2) | GrossSurfaceArea (m2) | GrossVolume (m3) | NetVolume (m3) = 체적 (m3) | NetSurfaceArea (m2) | 참조 레벨 | 작업 기준면 | 참조 레벨 입면도 (mm) | 보강 철근 피복 - 상단 면 | 절단 길이 (mm) | z 간격띄우기 값 (mm) | 상단 기준 레벨 (mm) | 하단 기준 레벨 (mm)
7668207 | 지하1층 | 7250 | 2500 | 0.28 | 5.5 | 6.06 | 0.7 | 1.73612 | 15.0425 | 지하1층 | 레벨 : 지하1층 | -6100 | 보강 철근 피복 1 <25 mm> | 6537.5 | 0 | -6100 | -6950
7668208 | 지하1층 | 7250 | 2500 | 0.28 | 5.5 | 6.06 | 0.7 | 1.764 | 14.98 | 지하1층 | 레벨 : 지하1층 | -6100 | 보강 철근 피복 1 <25 mm> | 6500 | 0 | -6100 | -6950
7668212 | 지하1층 | 7250 | 3700 | 0.28 | 8.14 | 8.7 | 1.036 | 1.792 | 15.2 | 지하1층 | 레벨 : 지하1층 | -6100 | 보강 철근 피복 1 <25 mm> | 6600 | 0 | -6100 | -6950
7668220 | 지하1층 | 5900 | 5900 | 0.245889 | 12.8013 | 13.2931 | 1.45074 | 1.4702 | 15.8705 | 지하1층 | 레벨 : 지하1층 | -6100 | 보강 철근 피복 1 <25 mm> | 5900 | 0 | -6100 | -6950
7668299 | 지상 1층 | 7250 | 2500 | 0.0527096 | 3.8765 | 3.98192 | 0.131774 | 0.315527 | 9.49293 | 지상 1층 | 레벨 : 지상 1층 | 0 |  | 6386.14 | 0 | 0 | -850
7668301 | 지상 1층 | 7250 | 2500 | 0.0527096 | 3.8765 | 3.98192 | 0.131774 | 0.317503 | 9.55105 | 지상 1층 | 레벨 : 지상 1층 | 0 | 보강 철근 피복 1 <25 mm> | 6423.62 | -500 | -500 | -1350
7668305 | 지상 1층 | 7250 | 313.865 | 0.0527096 | 0.486678 | 0.592098 | 0.0165437 | 0.316258 | 9.61985 | 지상 1층 | 레벨 : 지상 1층 | 0 |  | 6600 | 0 | 0 | -850
7669296 | 지하1층 | 6950 | 1200 | 0.269998 | 2.64 | 3.18 | 0.323998 | 1.68681 | 15.3645 | 지하1층 | 레벨 : 지하1층 | -6100 |  | 6537.5 | 0 | -6100 | -6950

# IfcBeam: BM111-철근콘크리트구조 보:BM110-철근 콘크리트구조 보_400 x 850_B1-1G4 (3)
In: 지상 1층
Type - PredefinedType: BEAM; Material: KBIMS-콘크리트 (2)
Type - ID 데이터 - 유형 마크: G4; 유형 이름: BM110-철근 콘크리트구조 보_400 x 850_B1-1G4
Type - 구조 - 단면 모양: 0
Type - 기타 - 내화구조여부: yes; 주요구조부여부: yes; 카테고리: 구조 프레임; KBIMS-부위코드: E23; 제작정보: bSK-2021_KBIMS2.0-bC; 조달청표준공사코드: AD; 패밀리 이름: BM111-철근콘크리트구조 보
Type - 재료 및 마감재 - 구조 재료: KBIMS-콘크리트
Type - 치수 - 가로치수: 400 mm; 세로치수: 850 mm
Type - Pset_BeamCommon - IsExternal: no; LoadBearing: yes
Pset_BeamCommon - Slope: 0 deg; Reference: BM110-철근 콘크리트구조 보_400 x 850_B1-1G4
Pset_QuantityTakeOff - Reference: BM110-철근 콘크리트구조 보_400 x 850_B1-1G4; sets with these values: 2
ID 데이터 - 연관 있음: no
공정 - 생성 공정: 새 구성
구속조건 - 끝 레벨 간격띄우기: 0 mm; 단면형상 회전: 0 deg; 방향: 보통; 시작 레벨 간격띄우기: 0 mm; 참조 레벨: 지상 1층; 참조 레벨 입면도: 0 mm; 작업 기준면: 레벨 : 지상 1층
구조 - 보강 철근 피복 - 다른 면: 보강 철근 피복 1 <25 mm>; 보강 철근 피복 - 하단 면: 보강 철근 피복 1 <25 mm>; 구조적 용도: 거더; 끝 부착 유형: 끝 입면
기타 - 패밀리: BM111-철근콘크리트구조 보; 유형: BM110-철근 콘크리트구조 보_400 x 850_B1-1G4; 유형 ID: 7667204; 패밀리 및 유형: BM111-철근콘크리트구조 보: BM110-철근 콘크리트구조 보_400 x 850_B1-1G4
기하학적 위치 - yz 맞춤: 균일; y 간격띄우기 값: 0 mm; y 맞춤: 원점; z 맞춤: 상단; 결합 상태: 두 결합 모두 사용
치수 - 단면적: 0.34 m2
Name (BM111-철근콘크리트구조 보:BM110-철근 콘크리트구조 보_400 x 850_B1-1G4:...) | Span (mm) = 길이 (mm) | CrossSectionArea (m2) | NetVolume (m3) = 체적 (m3) | NetSurfaceArea (m2) | 절단 길이 (mm) | z 간격띄우기 값 (mm) = 상단 기준 레벨 (mm) | 하단 기준 레벨 (mm) | 시작 부착 유형
7667172 | 7118 | 0.28 | 1.16399 | 12.589 | 6486.15 | 0 | -850 | BaseQuantities - Length: 1816.99 mm; OuterSurfaceArea: 3.99739 m2; GrossSurfaceArea: 4.55739 m2; GrossVolume: 0.508758 m3
7668300 | 7250 | 5.1221 | 0.342102 | 10.2442 | 6537.5 | -500 | -1350 | 끝 입면 | 구조 - 보강 철근 피복 - 상단 면: 보강 철근 피복 1 <25 mm>
7668317 | 7400 | 4.92902 | 0.327435 | 9.85804 | 6650.84 | 0 | -850 | 끝 입면

# IfcBeam: BM111-철근콘크리트구조 보:BM110-철근 콘크리트구조 보_400 x 850_B1-1G4, BM111-철근콘크리트구조 보:BM110-철근 콘크리트구조 보_400 x 850_B1-1G4:7667167
In: 지상 1층
Type - PredefinedType: BEAM; Material: KBIMS-콘크리트 (3)
Type - ID 데이터 - 유형 마크: G4; 유형 이름: BM110-철근 콘크리트구조 보_400 x 850_B1-1G4
Type - 구조 - 단면 모양: 0
Type - 기타 - 내화구조여부: yes; 주요구조부여부: yes; 카테고리: 구조 프레임; KBIMS-부위코드: E23; 제작정보: bSK-2021_KBIMS2.0-bC; 조달청표준공사코드: AD; 패밀리 이름: BM111-철근콘크리트구조 보
Type - 재료 및 마감재 - 구조 재료: KBIMS-콘크리트
Type - 치수 - 가로치수: 400 mm; 세로치수: 850 mm
Type - Pset_BeamCommon - IsExternal: no; LoadBearing: yes
Pset_BeamCommon - Slope: 0 deg; Reference: BM110-철근 콘크리트구조 보_400 x 850_B1-1G4; Span: 7250 mm
Pset_QuantityTakeOff - Reference: BM110-철근 콘크리트구조 보_400 x 850_B1-1G4; sets with these values: 2
BaseQuantities - Length: 2.39291 mm; CrossSectionArea: 0.000259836 m2; OuterSurfaceArea: 0.00335185 m2; GrossSurfaceArea: 0.00387152 m2; GrossVolume: 6.21763e-07 m3; NetVolume: 1.7965 m3; NetSurfaceArea: 15.3371 m2
ID 데이터 - 연관 있음: no
공정 - 생성 공정: 새 구성
구속조건 - 끝 레벨 간격띄우기: 0 mm; 단면형상 회전: 0 deg; 방향: 보통; 시작 레벨 간격띄우기: 0 mm; 참조 레벨: 지상 1층; 참조 레벨 입면도: 0 mm; 작업 기준면: 레벨 : 지상 1층
구조 - 보강 철근 피복 - 다른 면: 보강 철근 피복 1 <25 mm>; 보강 철근 피복 - 상단 면: 보강 철근 피복 1 <25 mm>; 보강 철근 피복 - 하단 면: 보강 철근 피복 1 <25 mm>; 시작 부착 유형: 끝 입면; 구조적 용도: 거더; 끝 부착 유형: 끝 입면; 절단 길이: 7088.39 mm
기타 - 패밀리: BM111-철근콘크리트구조 보; 유형: BM110-철근 콘크리트구조 보_400 x 850_B1-1G4; 유형 ID: 7667204; 패밀리 및 유형: BM111-철근콘크리트구조 보: BM110-철근 콘크리트구조 보_400 x 850_B1-1G4
기하학적 위치 - yz 맞춤: 균일; y 간격띄우기 값: 0 mm; y 맞춤: 원점; z 간격띄우기 값: 0 mm; z 맞춤: 상단; 결합 상태: 두 결합 모두 사용
치수 - 상단 기준 레벨: 0 mm; 길이: 7250 mm; 단면적: 0.34 m2; 체적: 1.7965 m3; 하단 기준 레벨: -850 mm

# IfcBeam: BM111-철근콘크리트구조 보:BM110-철근 콘크리트구조 보_400 x 850_B1-1G4, BM111-철근콘크리트구조 보:BM110-철근 콘크리트구조 보_400 x 850_B1-1G4:7668316
In: 지상 1층
Type - PredefinedType: BEAM; Material: KBIMS-콘크리트 (4)
Type - ID 데이터 - 유형 마크: G4; 유형 이름: BM110-철근 콘크리트구조 보_400 x 850_B1-1G4
Type - 구조 - 단면 모양: 0
Type - 기타 - 내화구조여부: yes; 주요구조부여부: yes; 카테고리: 구조 프레임; KBIMS-부위코드: E23; 제작정보: bSK-2021_KBIMS2.0-bC; 조달청표준공사코드: AD; 패밀리 이름: BM111-철근콘크리트구조 보
Type - 재료 및 마감재 - 구조 재료: KBIMS-콘크리트
Type - 치수 - 가로치수: 400 mm; 세로치수: 850 mm
Type - Pset_BeamCommon - IsExternal: no; LoadBearing: yes
Pset_BeamCommon - Slope: 0 deg; Reference: BM110-철근 콘크리트구조 보_400 x 850_B1-1G4; Span: 7617 mm
Pset_QuantityTakeOff - Reference: BM110-철근 콘크리트구조 보_400 x 850_B1-1G4; sets with these values: 2
BaseQuantities - Length: 1794.68 mm; CrossSectionArea: 0.0472547 m2; OuterSurfaceArea: 2.75486 m2; GrossSurfaceArea: 2.84937 m2; GrossVolume: 0.0848072 m3; NetVolume: 0.102482 m3; NetSurfaceArea: 3.66761 m2
ID 데이터 - 연관 있음: no
공정 - 생성 공정: 새 구성
구속조건 - 끝 레벨 간격띄우기: 0 mm; 단면형상 회전: 0 deg; 방향: 보통; 시작 레벨 간격띄우기: 0 mm; 참조 레벨: 지상 1층; 참조 레벨 입면도: 0 mm; 작업 기준면: 레벨 : 지상 1층
구조 - 보강 철근 피복 - 다른 면: 보강 철근 피복 1 <25 mm>; 보강 철근 피복 - 하단 면: 보강 철근 피복 1 <25 mm>; 시작 부착 유형: 끝 입면; 구조적 용도: 거더; 끝 부착 유형: 끝 입면; 절단 길이: 7643.93 mm
기타 - 패밀리: BM111-철근콘크리트구조 보; 유형: BM110-철근 콘크리트구조 보_400 x 850_B1-1G4; 유형 ID: 7667204; 패밀리 및 유형: BM111-철근콘크리트구조 보: BM110-철근 콘크리트구조 보_400 x 850_B1-1G4
기하학적 위치 - yz 맞춤: 균일; y 간격띄우기 값: 0 mm; y 맞춤: 원점; z 간격띄우기 값: 0 mm; z 맞춤: 상단; 결합 상태: 두 결합 모두 사용
치수 - 상단 기준 레벨: 0 mm; 길이: 7617 mm; 단면적: 0.34 m2; 체적: 0.102482 m3; 하단 기준 레벨: -850 mm

# IfcBeam: BM111-철근콘크리트구조 보:BM110-철근 콘크리트구조 보_400 x 850_B1-1G4 (8)
Type - ID 데이터 - 유형 마크: G4; 유형 이름: BM110-철근 콘크리트구조 보_400 x 850_B1-1G4
Type - 구조 - 단면 모양: 0
Type - 기타 - 내화구조여부: yes; 주요구조부여부: yes; 카테고리: 구조 프레임; KBIMS-부위코드: E23; 제작정보: bSK-2021_KBIMS2.0-bC; 조달청표준공사코드: AD; 패밀리 이름: BM111-철근콘크리트구조 보
Type - 재료 및 마감재 - 구조 재료: KBIMS-콘크리트
Type - 치수 - 가로치수: 400 mm; 세로치수: 850 mm
Type - Pset_BeamCommon - IsExternal: no; LoadBearing: yes
Material: KBIMS-콘크리트
Pset_BeamCommon - Slope: 0 deg; Reference: BM110-철근 콘크리트구조 보_400 x 850_B1-1G4
Pset_QuantityTakeOff - Reference: BM110-철근 콘크리트구조 보_400 x 850_B1-1G4; sets with these values: 2
ID 데이터 - 연관 있음: no
공정 - 생성 공정: 새 구성
구속조건 - 끝 레벨 간격띄우기: 0 mm; 단면형상 회전: 0 deg; 방향: 보통; 시작 레벨 간격띄우기: 0 mm
구조 - 보강 철근 피복 - 다른 면: 보강 철근 피복 1 <25 mm>; 보강 철근 피복 - 하단 면: 보강 철근 피복 1 <25 mm>; 구조적 용도: 거더; 끝 부착 유형: 끝 입면
기타 - 패밀리: BM111-철근콘크리트구조 보; 유형: BM110-철근 콘크리트구조 보_400 x 850_B1-1G4; 유형 ID: 7667204; 패밀리 및 유형: BM111-철근콘크리트구조 보: BM110-철근 콘크리트구조 보_400 x 850_B1-1G4
기하학적 위치 - yz 맞춤: 균일; y 간격띄우기 값: 0 mm; y 맞춤: 원점; z 맞춤: 상단; 결합 상태: 두 결합 모두 사용
치수 - 단면적: 0.34 m2
Name (BM111-철근콘크리트구조 보:BM110-철근 콘크리트구조 보_400 x 850_B1-1G4:...) | In | CrossSectionArea (m2) | NetVolume (m3) = 체적 (m3) | Span (mm) = 길이 (mm) | 참조 레벨 | 참조 레벨 입면도 (mm) | 작업 기준면 | 보강 철근 피복 - 상단 면 | 시작 부착 유형 | 절단 길이 (mm) | z 간격띄우기 값 (mm) | 상단 기준 레벨 (mm) | 하단 기준 레벨 (mm)
7667160 | 지상 1층 | 7.80217 | 1.79891 | 7150 | 지상 1층 | 0 | 레벨 : 지상 1층 | 보강 철근 피복 1 <25 mm> | 끝 입면 | 6900 | 0 | 0 | -850
7667161 | 지상 1층 | 7.54797 | 1.80458 | 7250 | 지상 1층 | 0 | 레벨 : 지상 1층 | 보강 철근 피복 1 <25 mm> | 끝 입면 | 6700 | 0 | 0 | -850
7667162 | 지상 1층 | 7.90625 | 1.9805 | 7150 | 지상 1층 | 0 | 레벨 : 지상 1층 | 보강 철근 피복 1 <25 mm> | 끝 입면 | 6537.5 | -500 | -500 | -1350
7667163 | 지상 1층 | 0.28 | 1.79858 | 7150 | 지상 1층 | 0 | 레벨 : 지상 1층 | 보강 철근 피복 1 <25 mm> | 끝 입면 | 6423.5 | -500 | -500 | -1350
7667173 | 지상 1층 | 7.48774 | 1.82593 | 7194 | 지상 1층 | 0 | 레벨 : 지상 1층 | 보강 철근 피복 1 <25 mm> |  | 6710.99 | 0 | 0 | -850
7668206 | 지하1층 | 0.28 | 1.82 | 7250 | 지하1층 | -6100 | 레벨 : 지하1층 | 보강 철근 피복 1 <25 mm> | 끝 입면 | 6500 | 0 | -6100 | -6950
7668219 | 지하1층 | 0.28 | 1.652 | 5900 | 지하1층 | -6100 | 레벨 : 지하1층 | 보강 철근 피복 1 <25 mm> | 끝 입면 | 5900 | 0 | -6100 | -6950
7668298 | 지상 1층 | 0.0527096 | 0.336611 | 7200 | 지상 1층 | 0 | 레벨 : 지상 1층 |  | 끝 입면 | 6386.14 | 0 | 0 | -850

# IfcBeam: BM111-철근콘크리트구조 보:BM110-철근 콘크리트구조 보_400 x 850_B1-1WG1 (16)
Type - PredefinedType: BEAM; Material: KBIMS-콘크리트
Type - ID 데이터 - 유형 마크: WG1; 유형 이름: BM110-철근 콘크리트구조 보_400 x 850_B1-1WG1
Type - 구조 - 단면 모양: 0
Type - 기타 - 내화구조여부: yes; 주요구조부여부: yes; 카테고리: 구조 프레임; KBIMS-부위코드: E23; 제작정보: bSK-2021_KBIMS2.0-bC; 조달청표준공사코드: AD; 패밀리 이름: BM111-철근콘크리트구조 보
Type - 재료 및 마감재 - 구조 재료: KBIMS-콘크리트
Type - 치수 - 가로치수: 400 mm; 세로치수: 850 mm
Type - Pset_BeamCommon - IsExternal: no; LoadBearing: yes
Pset_BeamCommon - Reference: BM110-철근 콘크리트구조 보_400 x 850_B1-1WG1
Pset_QuantityTakeOff - Reference: BM110-철근 콘크리트구조 보_400 x 850_B1-1WG1; sets with these values: 2
ID 데이터 - 연관 있음: no
공정 - 생성 공정: 새 구성
구속조건 - 끝 레벨 간격띄우기: 0 mm; 단면형상 회전: 0 deg
구조 - 보강 철근 피복 - 다른 면: 보강 철근 피복 1 <25 mm>
기타 - 패밀리: BM111-철근콘크리트구조 보; 유형: BM110-철근 콘크리트구조 보_400 x 850_B1-1WG1; 유형 ID: 7667206; 패밀리 및 유형: BM111-철근콘크리트구조 보: BM110-철근 콘크리트구조 보_400 x 850_B1-1WG1
기하학적 위치 - yz 맞춤: 균일; y 간격띄우기 값: 0 mm; y 맞춤: 원점; z 맞춤: 상단
치수 - 단면적: 0.34 m2
Name (BM111-철근콘크리트구조 보:BM110-철근 콘크리트구조 보_400 x 850_B1-1WG1:...) | In | Slope (deg) | Span (mm) = 길이 (mm) | CrossSectionArea (m2) | NetVolume (m3) = 체적 (m3) | 방향 | 시작 레벨 간격띄우기 (mm) | 참조 레벨 | 참조 레벨 입면도 (mm) | 작업 기준면 | 보강 철근 피복 - 상단 면 | 보강 철근 피복 - 하단 면 | 구조적 용도 | 절단 길이 (mm) | z 간격띄우기 값 (mm) | 결합 상태 | 상단 기준 레벨 (mm) | 하단 기준 레벨 (mm)
7667170 | 지상 1층 | 0 | 8353 | 0.28 | 2.0469 | 보통 | 0 | 지상 1층 | 0 | 레벨 : 지상 1층 | 보강 철근 피복 1 <25 mm> | 보강 철근 피복 1 <25 mm> | 거더 | 8128.29 | 0 | 두 결합 모두 사용 | 0 | -850 | BaseQuantities - Length: 5937.48 mm; OuterSurfaceArea: 13.0624 m2; GrossSurfaceArea: 13.6224 m2; GrossVolume: 1.66249 m3; NetSurfaceArea: 17.6912 m2; 구조 - 시작 부착 유형: 끝 입면
7667179 | 지상 1층 | 0 | 12249 | 0.0117851 | 0.138318 | 보통 | 0 | 지상 1층 | 0 | 레벨 : 지상 1층 | 보강 철근 피복 1 <25 mm> | 보강 철근 피복 1 <25 mm> | 거더 | 11736.7 | -450 | 두 결합 모두 사용 | -450 | -1300 | 구조 - 끝 부착 유형: 끝 입면
7667180 | 지상 1층 | 0 | 2550 | 0.0117851 | 0.0247369 | 보통 | 0 | 지상 1층 | 0 | 레벨 : 지상 1층 | 보강 철근 피복 1 <25 mm> | 보강 철근 피복 1 <25 mm> | 거더 | 2099 | -450 | 두 결합 모두 사용 | -450 | -1300 | 구조 - 시작 부착 유형: 끝 입면; 끝 부착 유형: 끝 입면
7667183 | 지상 1층 | 0 | 7600 | 0.14 | 0.98 | 보통 | 0 | 지상 1층 | 0 | 레벨 : 지상 1층 |  | 보강 철근 피복 1 <25 mm> | 기타 | 7200 | 0 | 두 결합 모두 사용 | 0 | -850 | BaseQuantities - Length: 4213.86 mm; OuterSurfaceArea: 7.58496 m2; GrossSurfaceArea: 7.86496 m2; GrossVolume: 0.589941 m3; NetSurfaceArea: 13.16 m2
7667184 | 지상 1층 | 0 | 6686 | 7.8239 | 1.53961 | 보통 | 0 | 지상 1층 | 0 | 레벨 : 지상 1층 | 보강 철근 피복 1 <25 mm> | 보강 철근 피복 1 <25 mm> | 기타 | 6986.14 | -550 | 두 결합 모두 사용 | -550 | -1400
7667190 | 지상 1층 | 0 | 10950 | 9.51514 | 1.00873 | 보통 | 0 | 지상 1층 | 0 | 레벨 : 지상 1층 | 보강 철근 피복 1 <25 mm> | 보강 철근 피복 1 <25 mm> | 기타 | 10962.7 | -550 | 하나 또는 두 개의 결합 사용 안 함 | -550 | -1400 | 구조 - 끝 부착 유형: 끝 입면
7667201 | 지상 1층 | 0 | 214 | 0.0687133 | 0.0129198 | 보통 | 0 | 지상 1층 | 0 | 레벨 : 지상 1층 | 보강 철근 피복 1 <25 mm> | 보강 철근 피복 1 <25 mm> | 기타 | 513.865 | -550 | 두 결합 모두 사용 | -550 | -1400 | BaseQuantities - Length: 113.865 mm; OuterSurfaceArea: 0.204959 m2; GrossSurfaceArea: 0.342385 m2; GrossVolume: 0.00782403 m3; NetSurfaceArea: 0.610072 m2
7668223 | 지하1층 | 0 | 7800 | 0.26 | 1.872 | 보통 | 0 | 지하1층 | -6100 | 레벨 : 지하1층 |  | 보강 철근 피복 1 <25 mm> | 거더 | 7200 | 0 | 두 결합 모두 사용 | -6100 | -6950 | 구조 - 시작 부착 유형: 끝 입면; 끝 부착 유형: 끝 입면
7668314 | 지상 1층 | 0 | 8016 | 0.0576737 | 0.421072 | 보통 | 0 | 지상 1층 | 0 | 레벨 : 지상 1층 |  | 보강 철근 피복 1 <25 mm> | 거더 | 7506.58 | 0 | 두 결합 모두 사용 | 0 | -850 | BaseQuantities - Length: 1394.2 mm; OuterSurfaceArea: 2.18162 m2; GrossSurfaceArea: 2.29697 m2; GrossVolume: 0.0804088 m3; NetSurfaceArea: 11.6555 m2; 구조 - 시작 부착 유형: 끝 입면
7668323 | 지상 1층 | 0 | 12250 | 6.60516 | 0.629145 | 보통 | 0 | 지상 1층 | 0 | 레벨 : 지상 1층 | 보강 철근 피복 1 <25 mm> | 보강 철근 피복 1 <25 mm> | 거더 | 6499.98 | -450 | 두 결합 모두 사용 | -450 | -1300 | 구조 - 시작 부착 유형: 끝 입면; 끝 부착 유형: 끝 입면
7668326 | 지상 1층 | 3.06981 | 3227 | 3.60445 | 0.321768 |  | -172.814 | 지상 1층 | 0 |  |  |  | 기타 | 3239.9 | 0 | 두 결합 모두 사용
7668327 | 지상 1층 | 0 | 4400 | 0.0527096 | 0.231922 | 보통 | 0 | 지상 1층 | 0 | 레벨 : 지상 1층 |  | 보강 철근 피복 1 <25 mm> | 기타 | 4400 | 0 | 두 결합 모두 사용 | 0 | -850
7668329 | 지상 1층 | 0 | 6667 | 0.379587 | 0.0284555 | 보통 | 0 | 지상 1층 | 0 | 레벨 : 지상 1층 | 보강 철근 피복 1 <25 mm> | 보강 철근 피복 1 <25 mm> | 기타 | 196.09 | -550 | 두 결합 모두 사용 | -550 | -1400
7668335 | 지상 1층 | 0 | 10950 | 0.065041 | 0.00155345 | 보통 | 0 | 지상 1층 | 0 | 레벨 : 지상 1층 |  | 보강 철근 피복 1 <25 mm> | 기타 | 75.2995 | -550 | 하나 또는 두 개의 결합 사용 안 함 | -550 | -1400 | 구조 - 끝 부착 유형: 끝 입면
7669302 | 지상 1층 | 0 | 7900 | 0.0967848 | 0.735751 | 보통 | 0 | 지상 1층 | 0 | 레벨 : 지상 1층 | 보강 철근 피복 1 <25 mm> | 보강 철근 피복 1 <25 mm> | 기타 | 7624.7 | 0 | 두 결합 모두 사용 | 0 | -850
7669316 | 지상 1층 | 0 | 133 | 0.0161217 | 0.000535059 | 보통 | 0 | 지상 1층 | 0 | 레벨 : 지상 1층 |  | 보강 철근 피복 1 <25 mm> | 기타 | 33.2822 | -550 | 두 결합 모두 사용 | -550 | -1400

# IfcBeam: BM111-철근콘크리트구조 보:BM110-철근 콘크리트구조 보_400 x 850_B1-1WG1 (3)
In: 지상 1층
Type - PredefinedType: BEAM; Material: KBIMS-콘크리트 (2)
Type - ID 데이터 - 유형 마크: WG1; 유형 이름: BM110-철근 콘크리트구조 보_400 x 850_B1-1WG1
Type - 구조 - 단면 모양: 0
Type - 기타 - 내화구조여부: yes; 주요구조부여부: yes; 카테고리: 구조 프레임; KBIMS-부위코드: E23; 제작정보: bSK-2021_KBIMS2.0-bC; 조달청표준공사코드: AD; 패밀리 이름: BM111-철근콘크리트구조 보
Type - 재료 및 마감재 - 구조 재료: KBIMS-콘크리트
Type - 치수 - 가로치수: 400 mm; 세로치수: 850 mm
Type - Pset_BeamCommon - IsExternal: no; LoadBearing: yes
Pset_BeamCommon - Reference: BM110-철근 콘크리트구조 보_400 x 850_B1-1WG1
Pset_QuantityTakeOff - Reference: BM110-철근 콘크리트구조 보_400 x 850_B1-1WG1; sets with these values: 2
ID 데이터 - 연관 있음: no
공정 - 생성 공정: 새 구성
구속조건 - 끝 레벨 간격띄우기: 0 mm; 단면형상 회전: 0 deg; 참조 레벨: 지상 1층; 참조 레벨 입면도: 0 mm
구조 - 보강 철근 피복 - 다른 면: 보강 철근 피복 1 <25 mm>
기타 - 패밀리: BM111-철근콘크리트구조 보; 유형: BM110-철근 콘크리트구조 보_400 x 850_B1-1WG1; 유형 ID: 7667206; 패밀리 및 유형: BM111-철근콘크리트구조 보: BM110-철근 콘크리트구조 보_400 x 850_B1-1WG1
기하학적 위치 - yz 맞춤: 균일; y 간격띄우기 값: 0 mm; y 맞춤: 원점; z 맞춤: 상단; 결합 상태: 두 결합 모두 사용
치수 - 단면적: 0.34 m2
Name (BM111-철근콘크리트구조 보:BM110-철근 콘크리트구조 보_400 x 850_B1-1WG1:...) | Span (mm) = 길이 (mm) | Slope (deg) | Length (mm) | CrossSectionArea (m2) | OuterSurfaceArea (m2) | GrossSurfaceArea (m2) | GrossVolume (m3) | NetVolume (m3) = 체적 (m3) | NetSurfaceArea (m2) | 시작 레벨 간격띄우기 (mm) | 구조적 용도 | 절단 길이 (mm) | z 간격띄우기 값 (mm) | 방향 | 작업 기준면 | 보강 철근 피복 - 상단 면 = 보강 철근 피복 - 하단 면 | 상단 기준 레벨 (mm) | 하단 기준 레벨 (mm)
7667181 | 2740 | 3.6161 | 2805.7 | 0.000400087 | 0.509403 | 0.510203 | 0.00112252 | 0.793077 | 7.41687 | -172.814 | 기타 | 2834.54 | 0
7668324 | 2549 | 0 |  | 2.01586 |  |  |  | 0.190908 | 4.03171 | 0 | 거더 | 2099.5 | -450 | 보통 | 레벨 : 지상 1층 | 보강 철근 피복 1 <25 mm> | -450 | -1300 | 구조 - 시작 부착 유형: 끝 입면; 끝 부착 유형: 끝 입면
7668328 | 7600 | 0 | 1.82063 | 1.39029 | 0.00978094 | 2.79037 | 0.00253122 | 0.010257 | 11.2994 | 0 | 기타 | 7400 | 0 | 보통 | 레벨 : 지상 1층 | 보강 철근 피복 1 <25 mm> | 0 | -850

# IfcBeam: BM111-철근콘크리트구조 보:BM110-철근 콘크리트구조 보_400 x 850_B1-1WG1 (2)
In: 지상 1층
Type - PredefinedType: BEAM; Material: KBIMS-콘크리트 (4)
Type - ID 데이터 - 유형 마크: WG1; 유형 이름: BM110-철근 콘크리트구조 보_400 x 850_B1-1WG1
Type - 구조 - 단면 모양: 0
Type - 기타 - 내화구조여부: yes; 주요구조부여부: yes; 카테고리: 구조 프레임; KBIMS-부위코드: E23; 제작정보: bSK-2021_KBIMS2.0-bC; 조달청표준공사코드: AD; 패밀리 이름: BM111-철근콘크리트구조 보
Type - 재료 및 마감재 - 구조 재료: KBIMS-콘크리트
Type - 치수 - 가로치수: 400 mm; 세로치수: 850 mm
Type - Pset_BeamCommon - IsExternal: no; LoadBearing: yes
Pset_BeamCommon - Slope: 0 deg; Reference: BM110-철근 콘크리트구조 보_400 x 850_B1-1WG1
Pset_QuantityTakeOff - Reference: BM110-철근 콘크리트구조 보_400 x 850_B1-1WG1; sets with these values: 2
ID 데이터 - 연관 있음: no
공정 - 생성 공정: 새 구성
구속조건 - 끝 레벨 간격띄우기: 0 mm; 단면형상 회전: 0 deg; 방향: 보통; 시작 레벨 간격띄우기: 0 mm; 참조 레벨: 지상 1층; 참조 레벨 입면도: 0 mm; 작업 기준면: 레벨 : 지상 1층
구조 - 보강 철근 피복 - 다른 면: 보강 철근 피복 1 <25 mm>; 보강 철근 피복 - 상단 면: 보강 철근 피복 1 <25 mm>; 보강 철근 피복 - 하단 면: 보강 철근 피복 1 <25 mm>; 구조적 용도: 기타
기타 - 패밀리: BM111-철근콘크리트구조 보; 유형: BM110-철근 콘크리트구조 보_400 x 850_B1-1WG1; 유형 ID: 7667206; 패밀리 및 유형: BM111-철근콘크리트구조 보: BM110-철근 콘크리트구조 보_400 x 850_B1-1WG1
기하학적 위치 - yz 맞춤: 균일; y 간격띄우기 값: 0 mm; y 맞춤: 원점; z 간격띄우기 값: 0 mm; z 맞춤: 상단; 결합 상태: 두 결합 모두 사용
치수 - 상단 기준 레벨: 0 mm; 단면적: 0.34 m2; 하단 기준 레벨: -850 mm
Name (BM111-철근콘크리트구조 보:BM110-철근 콘크리트구조 보_400 x 850_B1-1WG1:...) | Span (mm) = 길이 (mm) | Length (mm) | CrossSectionArea (m2) | OuterSurfaceArea (m2) | GrossSurfaceArea (m2) | GrossVolume (m3) | NetVolume (m3) = 체적 (m3) | NetSurfaceArea (m2) | 절단 길이 (mm)
7667182 | 4514 | 113.865 | 0.0539841 | 0.176973 | 0.284941 | 0.00614688 | 0.694914 | 16.0688 | 4913.86
7667199 | 7902 | 2424.73 | 0.100108 | 4.69318 | 4.89339 | 0.242735 | 1.42927 | 24.5287 | 7824.72

# IfcBeam: BM111-철근콘크리트구조 보:BM110-철근 콘크리트구조 보_500 x 400_2-10G11 (18)
Type - ID 데이터 - 유형 마크: G11; 유형 이름: BM110-철근 콘크리트구조 보_500 x 400_2-10G11
Type - 구조 - 단면 모양: 0
Type - 기타 - 내화구조여부: yes; 주요구조부여부: yes; 카테고리: 구조 프레임; KBIMS-부위코드: E23; 제작정보: bSK-2021_KBIMS2.0-bC; 조달청표준공사코드: AD; 패밀리 이름: BM111-철근콘크리트구조 보
Type - 재료 및 마감재 - 구조 재료: KBIMS-콘크리트
Type - 치수 - 가로치수: 500 mm; 세로치수: 400 mm
Type - Pset_BeamCommon - IsExternal: no; LoadBearing: yes
Material: KBIMS-콘크리트
Pset_BeamCommon - Slope: 0 deg; Reference: BM110-철근 콘크리트구조 보_500 x 400_2-10G11
Pset_QuantityTakeOff - Reference: BM110-철근 콘크리트구조 보_500 x 400_2-10G11; sets with these values: 2
ID 데이터 - 연관 있음: no
공정 - 생성 공정: 새 구성
구속조건 - 끝 레벨 간격띄우기: 0 mm; 단면형상 회전: 0 deg; 방향: 보통; 시작 레벨 간격띄우기: 0 mm
구조 - 보강 철근 피복 - 다른 면: 보강 철근 피복 1 <25 mm>; 보강 철근 피복 - 하단 면: 보강 철근 피복 1 <25 mm>; 시작 부착 유형: 끝 입면; 구조적 용도: 거더; 끝 부착 유형: 끝 입면
기타 - 패밀리: BM111-철근콘크리트구조 보; 유형: BM110-철근 콘크리트구조 보_500 x 400_2-10G11; 유형 ID: 7669426; 패밀리 및 유형: BM111-철근콘크리트구조 보: BM110-철근 콘크리트구조 보_500 x 400_2-10G11
기하학적 위치 - yz 맞춤: 균일; y 간격띄우기 값: 0 mm; y 맞춤: 원점; z 간격띄우기 값: 0 mm; z 맞춤: 상단; 결합 상태: 두 결합 모두 사용
치수 - 단면적: 0.2 m2
Name (BM111-철근콘크리트구조 보:BM110-철근 콘크리트구조 보_500 x 400_2-10G11:...) | In | CrossSectionArea (m2) | NetVolume (m3) = 체적 (m3) | Span (mm) = 길이 (mm) | 참조 레벨 | 작업 기준면 | 참조 레벨 입면도 (mm) = 상단 기준 레벨 (mm) | 절단 길이 (mm) | 하단 기준 레벨 (mm)
7668359 | 지상 2층 | 0.125 | 0.8125 | 7300 | 지상 2층 | 레벨 : 지상 2층 | 4800 | 6500 | 4400
7668360 | 지상 2층 | 0.125 | 0.8125 | 7250 | 지상 2층 | 레벨 : 지상 2층 | 4800 | 6500 | 4400 | 구조 - 보강 철근 피복 - 상단 면: 보강 철근 피복 1 <25 mm>
7668417 | 지상 3층 | 0.0937457 | 0.609347 | 6900 | 지상 3층 | 레벨 : 지상 3층 | 9300 | 6500 | 8900
7668418 | 지상 3층 | 0.125 | 0.8125 | 7100 | 지상 3층 | 레벨 : 지상 3층 | 9300 | 6500 | 8900 | 구조 - 보강 철근 피복 - 상단 면: 보강 철근 피복 1 <25 mm>
7668664 | 지상 4층 | 0.125 | 0.8125 | 6900 | 지상 4층 | 레벨 : 지상 4층 | 13400 | 6500 | 13000
7668665 | 지상 4층 | 0.125 | 0.8125 | 7100 | 지상 4층 | 레벨 : 지상 4층 | 13400 | 6500 | 13000 | 구조 - 보강 철근 피복 - 상단 면: 보강 철근 피복 1 <25 mm>
7668722 | 지상 5층 | 0.125 | 0.8125 | 6900 | 지상 5층 | 레벨 : 지상 5층 | 17500 | 6500 | 17100
7668723 | 지상 5층 | 0.125 | 0.8125 | 7100 | 지상 5층 | 레벨 : 지상 5층 | 17500 | 6500 | 17100 | 구조 - 보강 철근 피복 - 상단 면: 보강 철근 피복 1 <25 mm>
7668780 | 지상 6층 | 0.125 | 0.8125 | 6900 | 지상 6층 | 레벨 : 지상 6층 | 21600 | 6500 | 21200
7668781 | 지상 6층 | 0.125 | 0.8125 | 7100 | 지상 6층 | 레벨 : 지상 6층 | 21600 | 6500 | 21200 | 구조 - 보강 철근 피복 - 상단 면: 보강 철근 피복 1 <25 mm>
7668838 | 지상 7층 | 0.125 | 0.8125 | 6900 | 지상 7층 | 레벨 : 지상 7층 | 25700 | 6500 | 25300
7668839 | 지상 7층 | 0.125 | 0.8125 | 7100 | 지상 7층 | 레벨 : 지상 7층 | 25700 | 6500 | 25300 | 구조 - 보강 철근 피복 - 상단 면: 보강 철근 피복 1 <25 mm>
7668896 | 지상 8층 | 0.125 | 0.8125 | 6900 | 지상 8층 | 레벨 : 지상 8층 | 29800 | 6500 | 29400
7668897 | 지상 8층 | 0.125 | 0.8125 | 7100 | 지상 8층 | 레벨 : 지상 8층 | 29800 | 6500 | 29400 | 구조 - 보강 철근 피복 - 상단 면: 보강 철근 피복 1 <25 mm>
7668954 | 지상 9층 | 0.125 | 0.8125 | 6900 | 지상 9층 | 레벨 : 지상 9층 | 33900 | 6500 | 33500
7668955 | 지상 9층 | 0.125 | 0.812496 | 7100 | 지상 9층 | 레벨 : 지상 9층 | 33900 | 6499.97 | 33500 | 구조 - 보강 철근 피복 - 상단 면: 보강 철근 피복 1 <25 mm>
7669012 | 지상 10층 | 0.125 | 0.8125 | 6900 | 지상 10층 | 레벨 : 지상 10층 | 38400 | 6500 | 38000
7669013 | 지상 10층 | 0.125 | 0.812496 | 7100 | 지상 10층 | 레벨 : 지상 10층 | 38400 | 6499.97 | 38000 | 구조 - 보강 철근 피복 - 상단 면: 보강 철근 피복 1 <25 mm>

# IfcBeam: BM111-철근콘크리트구조 보:BM110-철근 콘크리트구조 보_500 x 400_2-10G5, BM111-철근콘크리트구조 보:BM110-철근 콘크리트구조 보_500 x 400_2-10G5:7668388
In: 지상 2층
Type - PredefinedType: BEAM; Material: KBIMS-콘크리트
Type - ID 데이터 - 유형 마크: G5; 유형 이름: BM110-철근 콘크리트구조 보_500 x 400_2-10G5
Type - 구조 - 단면 모양: 0
Type - 기타 - 내화구조여부: yes; 주요구조부여부: yes; 카테고리: 구조 프레임; KBIMS-부위코드: E23; 제작정보: bSK-2021_KBIMS2.0-bC; 조달청표준공사코드: AD; 패밀리 이름: BM111-철근콘크리트구조 보
Type - 재료 및 마감재 - 구조 재료: KBIMS-콘크리트
Type - 치수 - 가로치수: 500 mm; 세로치수: 400 mm
Type - Pset_BeamCommon - IsExternal: no; LoadBearing: yes
Pset_BeamCommon - Slope: 0 deg; Reference: BM110-철근 콘크리트구조 보_500 x 400_2-10G5; Span: 5300 mm
Pset_QuantityTakeOff - Reference: BM110-철근 콘크리트구조 보_500 x 400_2-10G5; sets with these values: 2
BaseQuantities - Length: 3199.99 mm; CrossSectionArea: 0.06 m2; OuterSurfaceArea: 3.19999 m2; GrossSurfaceArea: 3.31999 m2; GrossVolume: 0.191999 m3; NetVolume: 0.452499 m3; NetSurfaceArea: 8.38999 m2
ID 데이터 - 연관 있음: no
공정 - 생성 공정: 새 구성
구속조건 - 끝 레벨 간격띄우기: 0 mm; 단면형상 회전: 0 deg; 방향: 보통; 시작 레벨 간격띄우기: 0 mm; 참조 레벨: 지상 2층; 작업 기준면: 레벨 : 지상 2층; 참조 레벨 입면도: 4800 mm
구조 - 보강 철근 피복 - 다른 면: 보강 철근 피복 1 <25 mm>; 보강 철근 피복 - 상단 면: 보강 철근 피복 1 <25 mm>; 보강 철근 피복 - 하단 면: 보강 철근 피복 1 <25 mm>; 구조적 용도: 기타; 절단 길이: 5100 mm
기타 - 패밀리: BM111-철근콘크리트구조 보; 유형: BM110-철근 콘크리트구조 보_500 x 400_2-10G5; 유형 ID: 7669425; 패밀리 및 유형: BM111-철근콘크리트구조 보: BM110-철근 콘크리트구조 보_500 x 400_2-10G5
기하학적 위치 - yz 맞춤: 균일; y 간격띄우기 값: 0 mm; y 맞춤: 원점; z 간격띄우기 값: 0 mm; z 맞춤: 상단; 결합 상태: 두 결합 모두 사용
치수 - 길이: 5300 mm; 단면적: 0.2 m2; 상단 기준 레벨: 4800 mm; 체적: 0.452499 m3; 하단 기준 레벨: 4400 mm

# IfcBeam: BM111-철근콘크리트구조 보:BM110-철근 콘크리트구조 보_500 x 400_2-10G5 (18)
Type - ID 데이터 - 유형 마크: G5; 유형 이름: BM110-철근 콘크리트구조 보_500 x 400_2-10G5
Type - 구조 - 단면 모양: 0
Type - 기타 - 내화구조여부: yes; 주요구조부여부: yes; 카테고리: 구조 프레임; KBIMS-부위코드: E23; 제작정보: bSK-2021_KBIMS2.0-bC; 조달청표준공사코드: AD; 패밀리 이름: BM111-철근콘크리트구조 보
Type - 재료 및 마감재 - 구조 재료: KBIMS-콘크리트
Type - 치수 - 가로치수: 500 mm; 세로치수: 400 mm
Type - Pset_BeamCommon - IsExternal: no; LoadBearing: yes
Material: KBIMS-콘크리트
Pset_BeamCommon - Slope: 0 deg; Reference: BM110-철근 콘크리트구조 보_500 x 400_2-10G5
Pset_QuantityTakeOff - Reference: BM110-철근 콘크리트구조 보_500 x 400_2-10G5; sets with these values: 2
ID 데이터 - 연관 있음: no
공정 - 생성 공정: 새 구성
구속조건 - 끝 레벨 간격띄우기: 0 mm; 단면형상 회전: 0 deg; 방향: 보통; 시작 레벨 간격띄우기: 0 mm
구조 - 보강 철근 피복 - 다른 면: 보강 철근 피복 1 <25 mm>; 보강 철근 피복 - 하단 면: 보강 철근 피복 1 <25 mm>; 시작 부착 유형: 끝 입면; 구조적 용도: 거더; 끝 부착 유형: 끝 입면
기타 - 패밀리: BM111-철근콘크리트구조 보; 유형: BM110-철근 콘크리트구조 보_500 x 400_2-10G5; 유형 ID: 7669425; 패밀리 및 유형: BM111-철근콘크리트구조 보: BM110-철근 콘크리트구조 보_500 x 400_2-10G5
기하학적 위치 - yz 맞춤: 균일; y 간격띄우기 값: 0 mm; y 맞춤: 원점; z 간격띄우기 값: 0 mm; z 맞춤: 상단; 결합 상태: 두 결합 모두 사용
치수 - 단면적: 0.2 m2
Name (BM111-철근콘크리트구조 보:BM110-철근 콘크리트구조 보_500 x 400_2-10G5:...) | In | CrossSectionArea (m2) | NetVolume (m3) = 체적 (m3) | Span (mm) = 길이 (mm) | 참조 레벨 | 작업 기준면 | 참조 레벨 입면도 (mm) = 상단 기준 레벨 (mm) | 절단 길이 (mm) | 하단 기준 레벨 (mm)
7668367 | 지상 2층 | 0.0750022 | 0.604705 | 9300 | 지상 2층 | 레벨 : 지상 2층 | 4800 | 8062.5 | 4400
7668368 | 지상 2층 | 0.125 | 1.00781 | 8700 | 지상 2층 | 레벨 : 지상 2층 | 4800 | 8062.5 | 4400
7668425 | 지상 3층 | 0.0750022 | 0.607518 | 9400 | 지상 3층 | 레벨 : 지상 3층 | 9300 | 8100 | 8900
7668426 | 지상 3층 | 0.0937522 | 0.759393 | 8700 | 지상 3층 | 레벨 : 지상 3층 | 9300 | 8100 | 8900
7668672 | 지상 4층 | 0.0750022 | 0.607518 | 9300 | 지상 4층 | 레벨 : 지상 4층 | 13400 | 8100 | 13000
7668673 | 지상 4층 | 0.125 | 1.0125 | 8700 | 지상 4층 | 레벨 : 지상 4층 | 13400 | 8100 | 13000
7668730 | 지상 5층 | 4.58207 | 0.608018 | 9300 | 지상 5층 | 레벨 : 지상 5층 | 17500 | 8100 | 17100
7668731 | 지상 5층 | 0.125 | 1.0125 | 8700 | 지상 5층 | 레벨 : 지상 5층 | 17500 | 8100 | 17100
7668788 | 지상 6층 | 0.0750022 | 0.622518 | 9300 | 지상 6층 | 레벨 : 지상 6층 | 21600 | 8300 | 21200
7668789 | 지상 6층 | 0.125 | 1.0375 | 9100 | 지상 6층 | 레벨 : 지상 6층 | 21600 | 8300 | 21200
7668846 | 지상 7층 | 0.0750022 | 0.622518 | 9300 | 지상 7층 | 레벨 : 지상 7층 | 25700 | 8300 | 25300
7668847 | 지상 7층 | 0.125 | 1.0375 | 9100 | 지상 7층 | 레벨 : 지상 7층 | 25700 | 8300 | 25300
7668904 | 지상 8층 | 0.0750022 | 0.622518 | 9300 | 지상 8층 | 레벨 : 지상 8층 | 29800 | 8300 | 29400
7668905 | 지상 8층 | 0.125 | 1.0375 | 9100 | 지상 8층 | 레벨 : 지상 8층 | 29800 | 8300 | 29400
7668962 | 지상 9층 | 0.0750022 | 0.622518 | 9300 | 지상 9층 | 레벨 : 지상 9층 | 33900 | 8300 | 33500
7668963 | 지상 9층 | 0.125 | 1.0375 | 9100 | 지상 9층 | 레벨 : 지상 9층 | 33900 | 8300 | 33500
7669020 | 지상 10층 | 4.69207 | 0.623018 | 9300 | 지상 10층 | 레벨 : 지상 10층 | 38400 | 8300 | 38000
7669021 | 지상 10층 | 0.125 | 1.0375 | 9100 | 지상 10층 | 레벨 : 지상 10층 | 38400 | 8300 | 38000

# IfcBeam: BM111-철근콘크리트구조 보:BM110-철근 콘크리트구조 보_500 x 400_2-10G9 (36)
Type - ID 데이터 - 유형 마크: G9; 유형 이름: BM110-철근 콘크리트구조 보_500 x 400_2-10G9
Type - 구조 - 단면 모양: 0
Type - 기타 - 내화구조여부: yes; 주요구조부여부: yes; 카테고리: 구조 프레임; KBIMS-부위코드: E23; 제작정보: bSK-2021_KBIMS2.0-bC; 조달청표준공사코드: AD; 패밀리 이름: BM111-철근콘크리트구조 보
Type - 재료 및 마감재 - 구조 재료: KBIMS-콘크리트
Type - 치수 - 가로치수: 500 mm; 세로치수: 400 mm
Type - Pset_BeamCommon - IsExternal: no; LoadBearing: yes
Material: KBIMS-콘크리트
Pset_BeamCommon - Slope: 0 deg; Reference: BM110-철근 콘크리트구조 보_500 x 400_2-10G9
Pset_QuantityTakeOff - Reference: BM110-철근 콘크리트구조 보_500 x 400_2-10G9; sets with these values: 2
ID 데이터 - 연관 있음: no
공정 - 생성 공정: 새 구성
구속조건 - 끝 레벨 간격띄우기: 0 mm; 단면형상 회전: 0 deg; 방향: 보통; 시작 레벨 간격띄우기: 0 mm
구조 - 보강 철근 피복 - 다른 면: 보강 철근 피복 1 <25 mm>; 보강 철근 피복 - 하단 면: 보강 철근 피복 1 <25 mm>; 구조적 용도: 기타; 시작 부착 유형: 끝 입면; 끝 부착 유형: 끝 입면
기타 - 패밀리: BM111-철근콘크리트구조 보; 유형: BM110-철근 콘크리트구조 보_500 x 400_2-10G9; 유형 ID: 7669422; 패밀리 및 유형: BM111-철근콘크리트구조 보: BM110-철근 콘크리트구조 보_500 x 400_2-10G9
기하학적 위치 - yz 맞춤: 균일; y 간격띄우기 값: 0 mm; y 맞춤: 원점; z 간격띄우기 값: 0 mm; z 맞춤: 상단; 결합 상태: 두 결합 모두 사용
치수 - 단면적: 0.2 m2
Name (BM111-철근콘크리트구조 보:BM110-철근 콘크리트구조 보_500 x 400_2-10G9:...) | In | CrossSectionArea (m2) | NetVolume (m3) = 체적 (m3) | Span (mm) = 길이 (mm) | 참조 레벨 | 작업 기준면 | 참조 레벨 입면도 (mm) = 상단 기준 레벨 (mm) | 절단 길이 (mm) | 하단 기준 레벨 (mm)
7668340 | 지상 2층 | 0.125 | 1.2375 | 10102 | 지상 2층 | 레벨 : 지상 2층 | 4800 | 9900 | 4400
7668341 | 지상 2층 | 0.125 | 1.1375 | 10300 | 지상 2층 | 레벨 : 지상 2층 | 4800 | 9100.01 | 4400
7668345 | 지상 2층 | 0.125 | 1.23708 | 9900 | 지상 2층 | 레벨 : 지상 2층 | 4800 | 9896.67 | 4400 | 구조 - 보강 철근 피복 - 상단 면: 보강 철근 피복 1 <25 mm>
7668346 | 지상 2층 | 0.075 | 0.675 | 9503 | 지상 2층 | 레벨 : 지상 2층 | 4800 | 9000 | 4400
7668398 | 지상 3층 | 6.31475 | 0.928688 | 10102 | 지상 3층 | 레벨 : 지상 3층 | 9300 | 9900 | 8900
7668399 | 지상 3층 | 5.84826 | 0.854251 | 10300 | 지상 3층 | 레벨 : 지상 3층 | 9300 | 9100.01 | 8900
7668403 | 지상 3층 | 0.125 | 1.2375 | 10097 | 지상 3층 | 레벨 : 지상 3층 | 9300 | 9900 | 8900 | 구조 - 보강 철근 피복 - 상단 면: 보강 철근 피복 1 <25 mm>
7668404 | 지상 3층 | 0.125 | 1.1375 | 9703 | 지상 3층 | 레벨 : 지상 3층 | 9300 | 9100 | 8900
7668645 | 지상 4층 | 0.125 | 1.2375 | 10102 | 지상 4층 | 레벨 : 지상 4층 | 13400 | 9900 | 13000
7668646 | 지상 4층 | 0.125 | 1.1375 | 10300 | 지상 4층 | 레벨 : 지상 4층 | 13400 | 9100.01 | 13000
7668650 | 지상 4층 | 0.125 | 1.2375 | 9930 | 지상 4층 | 레벨 : 지상 4층 | 13400 | 9900 | 13000 | 구조 - 보강 철근 피복 - 상단 면: 보강 철근 피복 1 <25 mm>
7668651 | 지상 4층 | 0.125 | 1.1375 | 9703 | 지상 4층 | 레벨 : 지상 4층 | 13400 | 9100.01 | 13000
7668703 | 지상 5층 | 0.125 | 1.2375 | 10102 | 지상 5층 | 레벨 : 지상 5층 | 17500 | 9900 | 17100
7668704 | 지상 5층 | 0.125 | 1.1375 | 10300 | 지상 5층 | 레벨 : 지상 5층 | 17500 | 9100.01 | 17100
7668708 | 지상 5층 | 0.125 | 1.2375 | 10097 | 지상 5층 | 레벨 : 지상 5층 | 17500 | 9900 | 17100 | 구조 - 보강 철근 피복 - 상단 면: 보강 철근 피복 1 <25 mm>
7668709 | 지상 5층 | 0.125 | 1.1375 | 9703 | 지상 5층 | 레벨 : 지상 5층 | 17500 | 9100 | 17100
7668761 | 지상 6층 | 0.125 | 1.2375 | 10102 | 지상 6층 | 레벨 : 지상 6층 | 21600 | 9900 | 21200
7668762 | 지상 6층 | 8.9525 | 1.23375 | 10300 | 지상 6층 | 레벨 : 지상 6층 | 21600 | 10500 | 21200 | 구조 - 보강 철근 피복 - 상단 면: 보강 철근 피복 1 <25 mm>
7668766 | 지상 6층 | 0.125 | 1.2375 | 10097 | 지상 6층 | 레벨 : 지상 6층 | 21600 | 9900 | 21200 | 구조 - 보강 철근 피복 - 상단 면: 보강 철근 피복 1 <25 mm>
7668767 | 지상 6층 | 0.125 | 1.1375 | 9703 | 지상 6층 | 레벨 : 지상 6층 | 21600 | 9100 | 21200
7668819 | 지상 7층 | 0.125 | 1.2375 | 10102 | 지상 7층 | 레벨 : 지상 7층 | 25700 | 9900 | 25300
7668820 | 지상 7층 | 8.9525 | 1.23375 | 10300 | 지상 7층 | 레벨 : 지상 7층 | 25700 | 10500 | 25300 | 구조 - 보강 철근 피복 - 상단 면: 보강 철근 피복 1 <25 mm>
7668824 | 지상 7층 | 0.125 | 1.2375 | 10097 | 지상 7층 | 레벨 : 지상 7층 | 25700 | 9900 | 25300 | 구조 - 보강 철근 피복 - 상단 면: 보강 철근 피복 1 <25 mm>
7668825 | 지상 7층 | 0.125 | 1.1375 | 9703 | 지상 7층 | 레벨 : 지상 7층 | 25700 | 9100 | 25300
7668877 | 지상 8층 | 0.125 | 1.2375 | 10102 | 지상 8층 | 레벨 : 지상 8층 | 29800 | 9900 | 29400
7668878 | 지상 8층 | 8.9525 | 1.23375 | 10300 | 지상 8층 | 레벨 : 지상 8층 | 29800 | 10500 | 29400 | 구조 - 보강 철근 피복 - 상단 면: 보강 철근 피복 1 <25 mm>
7668882 | 지상 8층 | 0.125 | 1.2375 | 10097 | 지상 8층 | 레벨 : 지상 8층 | 29800 | 9900 | 29400 | 구조 - 보강 철근 피복 - 상단 면: 보강 철근 피복 1 <25 mm>
7668883 | 지상 8층 | 0.125 | 1.1375 | 9703 | 지상 8층 | 레벨 : 지상 8층 | 29800 | 9100 | 29400
7668935 | 지상 9층 | 0.125 | 1.25 | 10500 | 지상 9층 | 레벨 : 지상 9층 | 33900 | 10000 | 33500
7668936 | 지상 9층 | 9.0425 | 1.25625 | 10300 | 지상 9층 | 레벨 : 지상 9층 | 33900 | 10500 | 33500 | 구조 - 보강 철근 피복 - 상단 면: 보강 철근 피복 1 <25 mm>
7668940 | 지상 9층 | 0.125 | 1.25 | 10497 | 지상 9층 | 레벨 : 지상 9층 | 33900 | 10000 | 33500 | 구조 - 보강 철근 피복 - 상단 면: 보강 철근 피복 1 <25 mm>
7668941 | 지상 9층 | 0.125 | 1.1625 | 10100 | 지상 9층 | 레벨 : 지상 9층 | 33900 | 9300 | 33500
7668993 | 지상 10층 | 0.125 | 1.25 | 10500 | 지상 10층 | 레벨 : 지상 10층 | 38400 | 10000 | 38000
7668994 | 지상 10층 | 9.0425 | 1.25625 | 10300 | 지상 10층 | 레벨 : 지상 10층 | 38400 | 10500 | 38000 | 구조 - 보강 철근 피복 - 상단 면: 보강 철근 피복 1 <25 mm>
7668998 | 지상 10층 | 0.125 | 1.25 | 10497 | 지상 10층 | 레벨 : 지상 10층 | 38400 | 10000 | 38000 | 구조 - 보강 철근 피복 - 상단 면: 보강 철근 피복 1 <25 mm>
7668999 | 지상 10층 | 0.125 | 1.1625 | 10100 | 지상 10층 | 레벨 : 지상 10층 | 38400 | 9300 | 38000 | 구조 - 보강 철근 피복 - 상단 면: 보강 철근 피복 1 <25 mm>

# IfcBeam: BM111-철근콘크리트구조 보:BM110-철근 콘크리트구조 보_500 x 500_RG10 (4)
In: 옥탑층
Type - ID 데이터 - 유형 마크: G10; 유형 이름: BM110-철근 콘크리트구조 보_500 x 500_RG10
Type - 구조 - 단면 모양: 0
Type - 기타 - 내화구조여부: yes; 주요구조부여부: yes; 카테고리: 구조 프레임; KBIMS-부위코드: E23; 제작정보: bSK-2021_KBIMS2.0-bC; 조달청표준공사코드: AD; 패밀리 이름: BM111-철근콘크리트구조 보
Type - 재료 및 마감재 - 구조 재료: KBIMS-콘크리트
Type - 치수 - 가로치수: 500 mm; 세로치수: 500 mm
Type - Pset_BeamCommon - IsExternal: no; LoadBearing: yes
Material: KBIMS-콘크리트
Pset_BeamCommon - Slope: 0 deg; Reference: BM110-철근 콘크리트구조 보_500 x 500_RG10
Pset_QuantityTakeOff - Reference: BM110-철근 콘크리트구조 보_500 x 500_RG10; sets with these values: 2
ID 데이터 - 연관 있음: no
공정 - 생성 공정: 새 구성
구속조건 - 끝 레벨 간격띄우기: 0 mm; 단면형상 회전: 0 deg; 방향: 보통; 시작 레벨 간격띄우기: 0 mm; 참조 레벨: 옥탑층; 작업 기준면: 레벨 : 옥탑층; 참조 레벨 입면도: 43400 mm
구조 - 보강 철근 피복 - 다른 면: 보강 철근 피복 1 <25 mm>; 보강 철근 피복 - 하단 면: 보강 철근 피복 1 <25 mm>; 시작 부착 유형: 끝 입면; 구조적 용도: 거더; 끝 부착 유형: 끝 입면
기타 - 패밀리: BM111-철근콘크리트구조 보; 유형: BM110-철근 콘크리트구조 보_500 x 500_RG10; 유형 ID: 7669451; 패밀리 및 유형: BM111-철근콘크리트구조 보: BM110-철근 콘크리트구조 보_500 x 500_RG10
기하학적 위치 - yz 맞춤: 균일; y 간격띄우기 값: 0 mm; y 맞춤: 원점; z 간격띄우기 값: 0 mm; z 맞춤: 상단; 결합 상태: 두 결합 모두 사용
치수 - 단면적: 0.25 m2; 상단 기준 레벨: 43400 mm; 하단 기준 레벨: 42900 mm
Name (BM111-철근콘크리트구조 보:BM110-철근 콘크리트구조 보_500 x 500_RG10:...) | CrossSectionArea (m2) | NetVolume (m3) = 체적 (m3) | Span (mm) = 길이 (mm) | 절단 길이 (mm)
7669084 | 7.5325 | 1.266 | 7800 | 7800 | 구조 - 보강 철근 피복 - 상단 면: 보강 철근 피복 1 <25 mm>
7669085 | 0.175 | 1.19001 | 7400 | 6800.03
7669091 | 7.8675 | 1.34975 | 8200 | 8000 | 구조 - 보강 철근 피복 - 상단 면: 보강 철근 피복 1 <25 mm>
7669094 | 0.175 | 1.2775 | 8000 | 7300

# IfcBeam: BM111-철근콘크리트구조 보:BM110-철근 콘크리트구조 보_500 x 500_RG11 (2)
In: 옥탑층
Type - ID 데이터 - 유형 마크: G11; 유형 이름: BM110-철근 콘크리트구조 보_500 x 500_RG11
Type - 구조 - 단면 모양: 0
Type - 기타 - 내화구조여부: yes; 주요구조부여부: yes; 카테고리: 구조 프레임; KBIMS-부위코드: E23; 제작정보: bSK-2021_KBIMS2.0-bC; 조달청표준공사코드: AD; 패밀리 이름: BM111-철근콘크리트구조 보
Type - 재료 및 마감재 - 구조 재료: KBIMS-콘크리트
Type - 치수 - 가로치수: 500 mm; 세로치수: 500 mm
Type - Pset_BeamCommon - IsExternal: no; LoadBearing: yes
Material: KBIMS-콘크리트
Pset_BeamCommon - Slope: 0 deg; Reference: BM110-철근 콘크리트구조 보_500 x 500_RG11
Pset_QuantityTakeOff - Reference: BM110-철근 콘크리트구조 보_500 x 500_RG11; sets with these values: 2
ID 데이터 - 연관 있음: no
공정 - 생성 공정: 새 구성
구속조건 - 끝 레벨 간격띄우기: 0 mm; 단면형상 회전: 0 deg; 방향: 보통; 시작 레벨 간격띄우기: 0 mm; 참조 레벨: 옥탑층; 작업 기준면: 레벨 : 옥탑층; 참조 레벨 입면도: 43400 mm
구조 - 보강 철근 피복 - 다른 면: 보강 철근 피복 1 <25 mm>; 보강 철근 피복 - 하단 면: 보강 철근 피복 1 <25 mm>; 시작 부착 유형: 끝 입면; 구조적 용도: 거더; 끝 부착 유형: 끝 입면
기타 - 패밀리: BM111-철근콘크리트구조 보; 유형: BM110-철근 콘크리트구조 보_500 x 500_RG11; 유형 ID: 7669450; 패밀리 및 유형: BM111-철근콘크리트구조 보: BM110-철근 콘크리트구조 보_500 x 500_RG11
기하학적 위치 - yz 맞춤: 균일; y 간격띄우기 값: 0 mm; y 맞춤: 원점; z 간격띄우기 값: 0 mm; z 맞춤: 상단; 결합 상태: 두 결합 모두 사용
치수 - 단면적: 0.25 m2; 상단 기준 레벨: 43400 mm; 하단 기준 레벨: 42900 mm
Name (BM111-철근콘크리트구조 보:BM110-철근 콘크리트구조 보_500 x 500_RG11:...) | CrossSectionArea (m2) | NetVolume (m3) = 체적 (m3) | Span (mm) = 길이 (mm) | 절단 길이 (mm)
7669078 | 6.9025 | 1.19625 | 6900 | 6900 | 구조 - 보강 철근 피복 - 상단 면: 보강 철근 피복 1 <25 mm>
7669079 | 0.175 | 1.13749 | 7100 | 6499.97

# IfcBeam: BM111-철근콘크리트구조 보:BM110-철근 콘크리트구조 보_500 x 500_RG5 (2)
In: 옥탑층
Type - ID 데이터 - 유형 마크: G5; 유형 이름: BM110-철근 콘크리트구조 보_500 x 500_RG5
Type - 구조 - 단면 모양: 0
Type - 기타 - 내화구조여부: yes; 주요구조부여부: yes; 카테고리: 구조 프레임; KBIMS-부위코드: E23; 제작정보: bSK-2021_KBIMS2.0-bC; 조달청표준공사코드: AD; 패밀리 이름: BM111-철근콘크리트구조 보
Type - 재료 및 마감재 - 구조 재료: KBIMS-콘크리트
Type - 치수 - 가로치수: 500 mm; 세로치수: 500 mm
Type - Pset_BeamCommon - IsExternal: no; LoadBearing: yes
Material: KBIMS-콘크리트
Pset_BeamCommon - Slope: 0 deg; Reference: BM110-철근 콘크리트구조 보_500 x 500_RG5
Pset_QuantityTakeOff - Reference: BM110-철근 콘크리트구조 보_500 x 500_RG5; sets with these values: 2
ID 데이터 - 연관 있음: no
공정 - 생성 공정: 새 구성
구속조건 - 끝 레벨 간격띄우기: 0 mm; 단면형상 회전: 0 deg; 방향: 보통; 시작 레벨 간격띄우기: 0 mm; 참조 레벨: 옥탑층; 작업 기준면: 레벨 : 옥탑층; 참조 레벨 입면도: 43400 mm
구조 - 보강 철근 피복 - 다른 면: 보강 철근 피복 1 <25 mm>; 보강 철근 피복 - 하단 면: 보강 철근 피복 1 <25 mm>; 시작 부착 유형: 끝 입면; 구조적 용도: 거더; 끝 부착 유형: 끝 입면; 절단 길이: 8300 mm
기타 - 패밀리: BM111-철근콘크리트구조 보; 유형: BM110-철근 콘크리트구조 보_500 x 500_RG5; 유형 ID: 7669441; 패밀리 및 유형: BM111-철근콘크리트구조 보: BM110-철근 콘크리트구조 보_500 x 500_RG5
기하학적 위치 - yz 맞춤: 균일; y 간격띄우기 값: 0 mm; y 맞춤: 원점; z 간격띄우기 값: 0 mm; z 맞춤: 상단; 결합 상태: 두 결합 모두 사용
치수 - 단면적: 0.25 m2; 상단 기준 레벨: 43400 mm; 하단 기준 레벨: 42900 mm
Name (BM111-철근콘크리트구조 보:BM110-철근 콘크리트구조 보_500 x 500_RG5:...) | CrossSectionArea (m2) | NetVolume (m3) = 체적 (m3) | Span (mm) = 길이 (mm)
7669086 | 0.0983561 | 0.816356 | 9300
7669087 | 0.175 | 1.4525 | 9100

# IfcBeam: BM111-철근콘크리트구조 보:BM110-철근 콘크리트구조 보_500 x 500_RG9 (4)
In: 옥탑층
Type - ID 데이터 - 유형 마크: G9; 유형 이름: BM110-철근 콘크리트구조 보_500 x 500_RG9
Type - 구조 - 단면 모양: 0
Type - 기타 - 내화구조여부: yes; 주요구조부여부: yes; 카테고리: 구조 프레임; KBIMS-부위코드: E23; 제작정보: bSK-2021_KBIMS2.0-bC; 조달청표준공사코드: AD; 패밀리 이름: BM111-철근콘크리트구조 보
Type - 재료 및 마감재 - 구조 재료: KBIMS-콘크리트
Type - 치수 - 가로치수: 500 mm; 세로치수: 500 mm
Type - Pset_BeamCommon - IsExternal: no; LoadBearing: yes
Material: KBIMS-콘크리트
Pset_BeamCommon - Slope: 0 deg; Reference: BM110-철근 콘크리트구조 보_500 x 500_RG9
Pset_QuantityTakeOff - Reference: BM110-철근 콘크리트구조 보_500 x 500_RG9; sets with these values: 2
ID 데이터 - 연관 있음: no
공정 - 생성 공정: 새 구성
구속조건 - 끝 레벨 간격띄우기: 0 mm; 단면형상 회전: 0 deg; 방향: 보통; 시작 레벨 간격띄우기: 0 mm; 참조 레벨: 옥탑층; 작업 기준면: 레벨 : 옥탑층; 참조 레벨 입면도: 43400 mm
구조 - 보강 철근 피복 - 다른 면: 보강 철근 피복 1 <25 mm>; 보강 철근 피복 - 하단 면: 보강 철근 피복 1 <25 mm>; 구조적 용도: 기타; 시작 부착 유형: 끝 입면; 끝 부착 유형: 끝 입면
기타 - 패밀리: BM111-철근콘크리트구조 보; 유형: BM110-철근 콘크리트구조 보_500 x 500_RG9; 유형 ID: 7669443; 패밀리 및 유형: BM111-철근콘크리트구조 보: BM110-철근 콘크리트구조 보_500 x 500_RG9
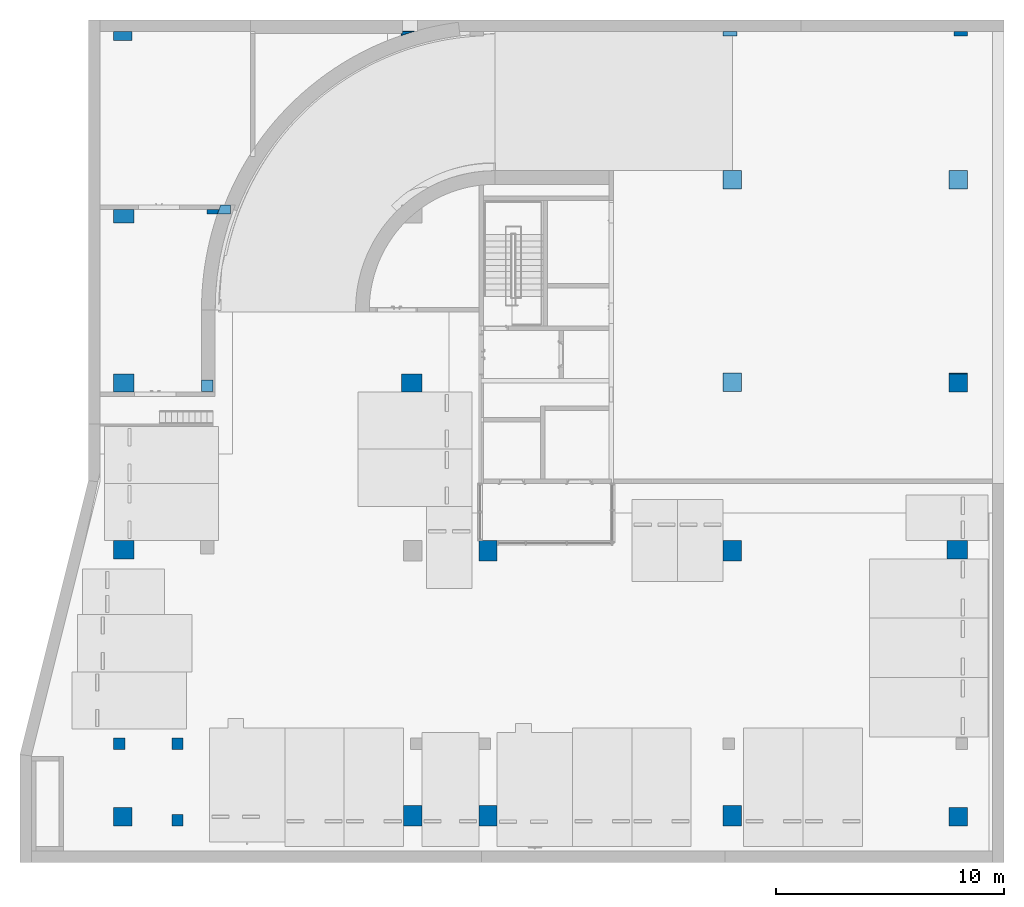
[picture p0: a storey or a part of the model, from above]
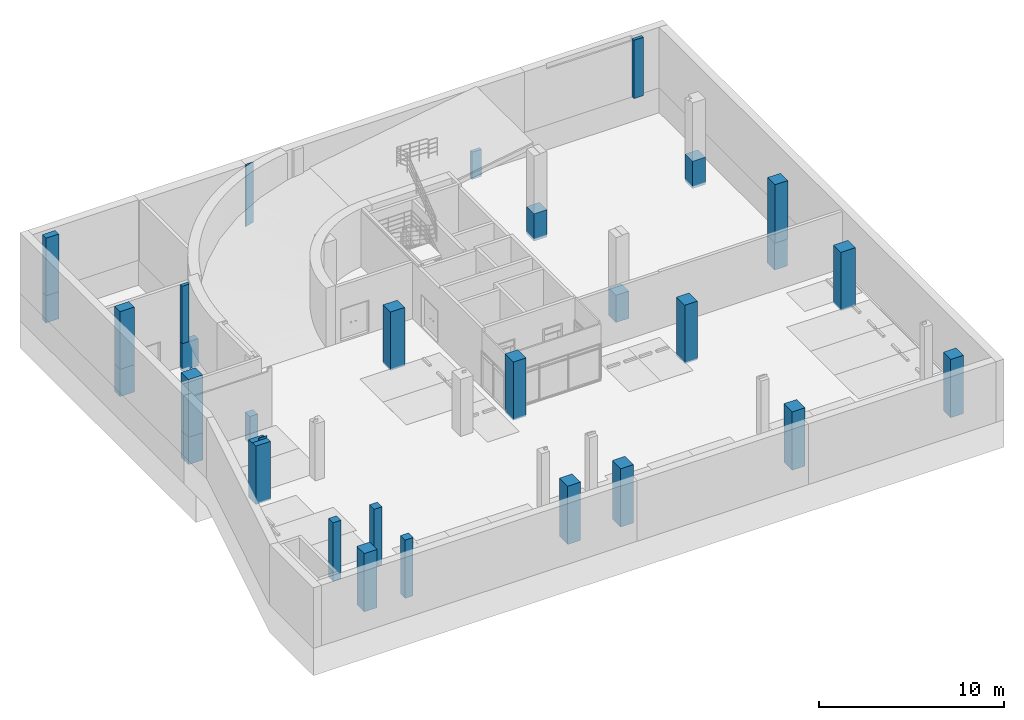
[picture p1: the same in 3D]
Properties of the parts of a building model (IFC2X3), part 9 of 39

# IfcBeam: BM111-철근콘크리트구조 보:BM110-철근 콘크리트구조 보_500 x 500_RG9 (4)
기하학적 위치 - yz 맞춤: 균일; y 간격띄우기 값: 0 mm; y 맞춤: 원점; z 간격띄우기 값: 0 mm; z 맞춤: 상단; 결합 상태: 두 결합 모두 사용
치수 - 단면적: 0.25 m2; 상단 기준 레벨: 43400 mm; 하단 기준 레벨: 42900 mm
Name (BM111-철근콘크리트구조 보:BM110-철근 콘크리트구조 보_500 x 500_RG9:...) | CrossSectionArea (m2) | NetVolume (m3) = 체적 (m3) | Span (mm) = 길이 (mm) | 절단 길이 (mm)
7669059 | 0.175 | 1.75 | 10500 | 10000
7669060 | 10.1425 | 1.72725 | 10300 | 10500 | 구조 - 보강 철근 피복 - 상단 면: 보강 철근 피복 1 <25 mm>
7669064 | 0.175 | 1.75 | 10497 | 10000
7669065 | 0.175 | 1.6275 | 10100 | 9300

# IfcBeam: BM111-철근콘크리트구조 보:BM110-철근 콘크리트구조 보_500 x 850_B1-1G5, BM111-철근콘크리트구조 보:BM110-철근 콘크리트구조 보_500 x 850_B1-1G5:7668274
In: 지상 1층
Type - PredefinedType: BEAM; Material: KBIMS-콘크리트
Type - ID 데이터 - 유형 마크: G5; 유형 이름: BM110-철근 콘크리트구조 보_500 x 850_B1-1G5
Type - 구조 - 단면 모양: 0
Type - 기타 - 내화구조여부: yes; 주요구조부여부: yes; 카테고리: 구조 프레임; KBIMS-부위코드: E23; 제작정보: bSK-2021_KBIMS2.0-bC; 조달청표준공사코드: AD; 패밀리 이름: BM111-철근콘크리트구조 보
Type - 재료 및 마감재 - 구조 재료: KBIMS-콘크리트
Type - 치수 - 가로치수: 500 mm; 세로치수: 850 mm
Type - Pset_BeamCommon - IsExternal: no; LoadBearing: yes
Pset_BeamCommon - Slope: 0 deg; Reference: BM110-철근 콘크리트구조 보_500 x 850_B1-1G5; Span: 9050 mm
Pset_QuantityTakeOff - Reference: BM110-철근 콘크리트구조 보_500 x 850_B1-1G5; sets with these values: 2
BaseQuantities - Length: 3166.67 mm; CrossSectionArea: 0.0797051 m2; OuterSurfaceArea: 5.15448 m2; GrossSurfaceArea: 5.31389 m2; GrossVolume: 0.2524 m3; NetVolume: 0.597789 m3; NetSurfaceArea: 12.6862 m2
ID 데이터 - 연관 있음: no
공정 - 생성 공정: 새 구성
구속조건 - 끝 레벨 간격띄우기: 0 mm; 단면형상 회전: 0 deg; 방향: 보통; 시작 레벨 간격띄우기: 0 mm; 참조 레벨: 지상 1층; 참조 레벨 입면도: 0 mm; 작업 기준면: 레벨 : 지상 1층
구조 - 보강 철근 피복 - 다른 면: 보강 철근 피복 1 <25 mm>; 보강 철근 피복 - 하단 면: 보강 철근 피복 1 <25 mm>; 구조적 용도: 기타; 시작 부착 유형: 끝 입면; 끝 부착 유형: 끝 입면; 절단 길이: 8300.01 mm
기타 - 패밀리: BM111-철근콘크리트구조 보; 유형: BM110-철근 콘크리트구조 보_500 x 850_B1-1G5; 유형 ID: 7667205; 패밀리 및 유형: BM111-철근콘크리트구조 보: BM110-철근 콘크리트구조 보_500 x 850_B1-1G5
기하학적 위치 - yz 맞춤: 균일; y 간격띄우기 값: 0 mm; y 맞춤: 원점; z 간격띄우기 값: 0 mm; z 맞춤: 상단; 결합 상태: 두 결합 모두 사용
치수 - 상단 기준 레벨: 0 mm; 길이: 9050 mm; 단면적: 0.425 m2; 체적: 0.597789 m3; 하단 기준 레벨: -850 mm

# IfcBeam: BM111-철근콘크리트구조 보:BM110-철근 콘크리트구조 보_500 x 850_B1-1G5 (2)
In: 지상 1층
Type - PredefinedType: BEAM; Material: KBIMS-콘크리트 (3)
Type - ID 데이터 - 유형 마크: G5; 유형 이름: BM110-철근 콘크리트구조 보_500 x 850_B1-1G5
Type - 구조 - 단면 모양: 0
Type - 기타 - 내화구조여부: yes; 주요구조부여부: yes; 카테고리: 구조 프레임; KBIMS-부위코드: E23; 제작정보: bSK-2021_KBIMS2.0-bC; 조달청표준공사코드: AD; 패밀리 이름: BM111-철근콘크리트구조 보
Type - 재료 및 마감재 - 구조 재료: KBIMS-콘크리트
Type - 치수 - 가로치수: 500 mm; 세로치수: 850 mm
Type - Pset_BeamCommon - IsExternal: no; LoadBearing: yes
Pset_BeamCommon - Slope: 0 deg; Reference: BM110-철근 콘크리트구조 보_500 x 850_B1-1G5
Pset_QuantityTakeOff - Reference: BM110-철근 콘크리트구조 보_500 x 850_B1-1G5; sets with these values: 2
ID 데이터 - 연관 있음: no
공정 - 생성 공정: 새 구성
구속조건 - 끝 레벨 간격띄우기: 0 mm; 단면형상 회전: 0 deg; 방향: 보통; 시작 레벨 간격띄우기: 0 mm; 참조 레벨: 지상 1층; 참조 레벨 입면도: 0 mm; 작업 기준면: 레벨 : 지상 1층
구조 - 보강 철근 피복 - 다른 면: 보강 철근 피복 1 <25 mm>; 보강 철근 피복 - 하단 면: 보강 철근 피복 1 <25 mm>; 구조적 용도: 기타; 시작 부착 유형: 끝 입면; 끝 부착 유형: 끝 입면
기타 - 패밀리: BM111-철근콘크리트구조 보; 유형: BM110-철근 콘크리트구조 보_500 x 850_B1-1G5; 유형 ID: 7667205; 패밀리 및 유형: BM111-철근콘크리트구조 보: BM110-철근 콘크리트구조 보_500 x 850_B1-1G5
기하학적 위치 - yz 맞춤: 균일; y 간격띄우기 값: 0 mm; y 맞춤: 원점; z 간격띄우기 값: 0 mm; z 맞춤: 상단; 결합 상태: 두 결합 모두 사용
치수 - 상단 기준 레벨: 0 mm; 단면적: 0.425 m2; 하단 기준 레벨: -850 mm
Name (BM111-철근콘크리트구조 보:BM110-철근 콘크리트구조 보_500 x 850_B1-1G5:...) | Span (mm) = 길이 (mm) | CrossSectionArea (m2) | NetVolume (m3) = 체적 (m3) | NetSurfaceArea (m2) | 절단 길이 (mm)
7668276 | 9900 | 0.0797051 | 0.742063 | 15.8743 | 9896.67 | BaseQuantities - Length: 3191.38 mm; OuterSurfaceArea: 5.1947 m2; GrossSurfaceArea: 5.35411 m2; GrossVolume: 0.254369 m3
7668277 | 9503 | 8.78159 | 1.19582 | 17.5632 | 9000

# IfcBeam: BM111-철근콘크리트구조 보:BM110-철근 콘크리트구조 보_500 x 850_B1-1G5 (19)
Type - ID 데이터 - 유형 마크: G5; 유형 이름: BM110-철근 콘크리트구조 보_500 x 850_B1-1G5
Type - 구조 - 단면 모양: 0
Type - 기타 - 내화구조여부: yes; 주요구조부여부: yes; 카테고리: 구조 프레임; KBIMS-부위코드: E23; 제작정보: bSK-2021_KBIMS2.0-bC; 조달청표준공사코드: AD; 패밀리 이름: BM111-철근콘크리트구조 보
Type - 재료 및 마감재 - 구조 재료: KBIMS-콘크리트
Type - 치수 - 가로치수: 500 mm; 세로치수: 850 mm
Type - Pset_BeamCommon - IsExternal: no; LoadBearing: yes
Material: KBIMS-콘크리트
Pset_BeamCommon - Slope: 0 deg; Reference: BM110-철근 콘크리트구조 보_500 x 850_B1-1G5
Pset_QuantityTakeOff - Reference: BM110-철근 콘크리트구조 보_500 x 850_B1-1G5; sets with these values: 2
ID 데이터 - 연관 있음: no
공정 - 생성 공정: 새 구성
구속조건 - 끝 레벨 간격띄우기: 0 mm; 단면형상 회전: 0 deg; 시작 레벨 간격띄우기: 0 mm
구조 - 보강 철근 피복 - 다른 면: 보강 철근 피복 1 <25 mm>; 보강 철근 피복 - 하단 면: 보강 철근 피복 1 <25 mm>
기타 - 패밀리: BM111-철근콘크리트구조 보; 유형: BM110-철근 콘크리트구조 보_500 x 850_B1-1G5; 유형 ID: 7667205; 패밀리 및 유형: BM111-철근콘크리트구조 보: BM110-철근 콘크리트구조 보_500 x 850_B1-1G5
기하학적 위치 - yz 맞춤: 균일; y 간격띄우기 값: 0 mm; y 맞춤: 원점; z 맞춤: 상단; 결합 상태: 두 결합 모두 사용
치수 - 단면적: 0.425 m2
Name (BM111-철근콘크리트구조 보:BM110-철근 콘크리트구조 보_500 x 850_B1-1G5:...) | In | CrossSectionArea (m2) | NetVolume (m3) = 체적 (m3) | Span (mm) = 길이 (mm) | 참조 레벨 | 참조 레벨 입면도 (mm) | 보강 철근 피복 - 상단 면 | 구조적 용도 | 시작 부착 유형 | 끝 부착 유형 | 절단 길이 (mm) | z 간격띄우기 값 (mm) | 상단 기준 레벨 (mm) | 하단 기준 레벨 (mm) | 방향 | 작업 기준면
7667131 | 지상 1층 | 13.3625 | 3.57857 | 10650 | 지상 1층 | 0 | 보강 철근 피복 1 <25 mm> | 기타 | 끝 입면 | 끝 입면 | 10900 | 0 | 0 | -850
7667133 | 지상 1층 | 13.3228 | 3.64176 | 10701 | 지상 1층 | 0 | 보강 철근 피복 1 <25 mm> | 기타 | 끝 입면 | 끝 입면 | 11100.4 | 0 | 0 | -850 | 보통 | 레벨 : 지상 1층
7667134 | 지상 1층 | 12.7342 | 3.45922 | 10300 | 지상 1층 | 0 | 보강 철근 피복 1 <25 mm> | 기타 | 끝 입면 | 끝 입면 | 10275 | 0 | 0 | -850 | 보통 | 레벨 : 지상 1층
7667136 | 지상 1층 | 11.5999 | 3.02222 | 9051 | 지상 1층 | 0 | 보강 철근 피복 1 <25 mm> | 기타 | 끝 입면 | 끝 입면 | 9525.88 | 0 | 0 | -850 | 보통 | 레벨 : 지상 1층
7667138 | 지상 1층 | 13.0099 | 3.46364 | 10096 | 지상 1층 | 0 | 보강 철근 피복 1 <25 mm> | 기타 |  | 끝 입면 | 10309 | 0 | 0 | -850 | 보통 | 레벨 : 지상 1층
7667139 | 지상 1층 | 13.1175 | 3.76303 | 9703 | 지상 1층 | 0 | 보강 철근 피복 1 <25 mm> | 기타 | 끝 입면 |  | 9715.88 | -500 | -500 | -1350 | 보통 | 레벨 : 지상 1층
7668170 | 지하1층 | 0.35 | 3.4825 | 10400 | 지하1층 | -6100 | 보강 철근 피복 1 <25 mm> | 기타 | 끝 입면 | 끝 입면 | 9950.01 | 0 | -6100 | -6950 | 보통 | 레벨 : 지하1층
7668172 | 지하1층 | 0.353638 | 3.60711 | 10700 | 지하1층 | -6100 | 보강 철근 피복 1 <25 mm> | 기타 | 끝 입면 | 끝 입면 | 10200 | 0 | -6100 | -6950 | 보통 | 레벨 : 지하1층
7668173 | 지하1층 | 0.353638 | 3.43029 | 9950 | 지하1층 | -6100 | 보강 철근 피복 1 <25 mm> | 기타 | 끝 입면 | 끝 입면 | 9700.01 | 0 | -6100 | -6950 | 보통 | 레벨 : 지하1층
7668177 | 지하1층 | 0.35 | 2.905 | 9050 | 지하1층 | -6100 |  | 기타 | 끝 입면 | 끝 입면 | 8300.01 | 0 | -6100 | -6950 | 보통 | 레벨 : 지하1층
7668179 | 지하1층 | 0.35 | 3.46384 | 10446 | 지하1층 | -6100 | 보강 철근 피복 1 <25 mm> | 기타 | 끝 입면 | 끝 입면 | 9896.67 | 0 | -6100 | -6950 | 보통 | 레벨 : 지하1층
7668180 | 지하1층 | 0.35 | 3.15 | 9503 | 지하1층 | -6100 |  | 기타 | 끝 입면 | 끝 입면 | 9000.01 | 0 | -6100 | -6950 | 보통 | 레벨 : 지하1층
7668213 | 지하1층 | 0.334999 | 2.70093 | 8700 | 지하1층 | -6100 |  | 거더 | 끝 입면 | 끝 입면 | 8062.5 | 0 | -6100 | -6950 | 보통 | 레벨 : 지하1층
7668214 | 지하1층 | 0.35 | 2.835 | 8700 | 지하1층 | -6100 | 보강 철근 피복 1 <25 mm> | 거더 | 끝 입면 | 끝 입면 | 8100 | 0 | -6100 | -6950 | 보통 | 레벨 : 지하1층
7668269 | 지상 1층 | 0.0797051 | 0.79105 | 10650 | 지상 1층 | 0 |  | 기타 | 끝 입면 | 끝 입면 | 9924.71 | 0 | 0 | -850
7668271 | 지상 1층 | 0.0797051 | 0.812993 | 10800 | 지상 1층 | 0 |  | 기타 | 끝 입면 | 끝 입면 | 10200 | 0 | 0 | -850 | 보통 | 레벨 : 지상 1층
7668272 | 지상 1층 | 8.2446 | 0.773219 | 10050 | 지상 1층 | 0 | 보강 철근 피복 1 <25 mm> | 기타 | 끝 입면 | 끝 입면 | 9700.01 | 0 | 0 | -850 | 보통 | 레벨 : 지상 1층
7668306 | 지상 1층 | 0.35 | 2.82188 | 9500 | 지상 1층 | 0 |  | 거더 | 끝 입면 | 끝 입면 | 8062.5 | -1500 | -1500 | -2350 | 보통 | 레벨 : 지상 1층
7668307 | 지상 1층 | 0.35 | 2.82188 | 8700 | 지상 1층 | 0 |  | 거더 | 끝 입면 | 끝 입면 | 8062.52 | -1500 | -1500 | -2350 | 보통 | 레벨 : 지상 1층

# IfcBeam: BM111-철근콘크리트구조 보:BM110-철근 콘크리트구조 보_600 x 400_2-10G12 (18)
Type - ID 데이터 - 유형 마크: G12; 유형 이름: BM110-철근 콘크리트구조 보_600 x 400_2-10G12
Type - 구조 - 단면 모양: 0
Type - 기타 - 내화구조여부: yes; 주요구조부여부: yes; 카테고리: 구조 프레임; KBIMS-부위코드: E23; 제작정보: bSK-2021_KBIMS2.0-bC; 조달청표준공사코드: AD; 패밀리 이름: BM111-철근콘크리트구조 보
Type - 재료 및 마감재 - 구조 재료: KBIMS-콘크리트
Type - 치수 - 가로치수: 600 mm; 세로치수: 400 mm
Type - Pset_BeamCommon - IsExternal: no; LoadBearing: yes
Material: KBIMS-콘크리트
Pset_BeamCommon - Slope: 0 deg; Reference: BM110-철근 콘크리트구조 보_600 x 400_2-10G12
Pset_QuantityTakeOff - Reference: BM110-철근 콘크리트구조 보_600 x 400_2-10G12; sets with these values: 2
ID 데이터 - 연관 있음: no
공정 - 생성 공정: 새 구성
구속조건 - 끝 레벨 간격띄우기: 0 mm; 단면형상 회전: 0 deg; 방향: 보통; 시작 레벨 간격띄우기: 0 mm
구조 - 보강 철근 피복 - 다른 면: 보강 철근 피복 1 <25 mm>; 보강 철근 피복 - 하단 면: 보강 철근 피복 1 <25 mm>; 시작 부착 유형: 끝 입면; 구조적 용도: 거더; 끝 부착 유형: 끝 입면
기타 - 패밀리: BM111-철근콘크리트구조 보; 유형: BM110-철근 콘크리트구조 보_600 x 400_2-10G12; 유형 ID: 7669411; 패밀리 및 유형: BM111-철근콘크리트구조 보: BM110-철근 콘크리트구조 보_600 x 400_2-10G12
기하학적 위치 - yz 맞춤: 균일; y 간격띄우기 값: 0 mm; y 맞춤: 원점; z 간격띄우기 값: 0 mm; z 맞춤: 상단; 결합 상태: 두 결합 모두 사용
치수 - 단면적: 0.24 m2
Name (BM111-철근콘크리트구조 보:BM110-철근 콘크리트구조 보_600 x 400_2-10G12:...) | In | CrossSectionArea (m2) | NetVolume (m3) = 체적 (m3) | Span (mm) = 길이 (mm) | 참조 레벨 | 작업 기준면 | 참조 레벨 입면도 (mm) = 상단 기준 레벨 (mm) | 절단 길이 (mm) | 하단 기준 레벨 (mm)
7668350 | 지상 2층 | 0.15 | 1.635 | 12050 | 지상 2층 | 레벨 : 지상 2층 | 4800 | 10900 | 4400
7668351 | 지상 2층 | 0.15 | 1.605 | 11850 | 지상 2층 | 레벨 : 지상 2층 | 4800 | 10700 | 4400
7668408 | 지상 3층 | 8.05456 | 1.29489 | 12100 | 지상 3층 | 레벨 : 지상 3층 | 9300 | 10900 | 8900
7668409 | 지상 3층 | 0.15 | 1.635 | 11850 | 지상 3층 | 레벨 : 지상 3층 | 9300 | 10900 | 8900
7668655 | 지상 4층 | 0.15 | 1.635 | 12100 | 지상 4층 | 레벨 : 지상 4층 | 13400 | 10900 | 13000
7668656 | 지상 4층 | 0.15 | 1.635 | 11850 | 지상 4층 | 레벨 : 지상 4층 | 13400 | 10900 | 13000
7668713 | 지상 5층 | 0.15 | 1.635 | 12100 | 지상 5층 | 레벨 : 지상 5층 | 17500 | 10900 | 17100
7668714 | 지상 5층 | 0.15 | 1.635 | 11850 | 지상 5층 | 레벨 : 지상 5층 | 17500 | 10900 | 17100
7668771 | 지상 6층 | 0.15 | 1.635 | 12100 | 지상 6층 | 레벨 : 지상 6층 | 21600 | 10900 | 21200
7668772 | 지상 6층 | 0.15 | 1.635 | 11850 | 지상 6층 | 레벨 : 지상 6층 | 21600 | 10900 | 21200
7668829 | 지상 7층 | 0.15 | 1.635 | 12100 | 지상 7층 | 레벨 : 지상 7층 | 25700 | 10900 | 25300
7668830 | 지상 7층 | 0.15 | 1.635 | 11850 | 지상 7층 | 레벨 : 지상 7층 | 25700 | 10900 | 25300
7668887 | 지상 8층 | 0.15 | 1.635 | 12100 | 지상 8층 | 레벨 : 지상 8층 | 29800 | 10900 | 29400
7668888 | 지상 8층 | 0.15 | 1.635 | 11850 | 지상 8층 | 레벨 : 지상 8층 | 29800 | 10900 | 29400
7668945 | 지상 9층 | 0.15 | 1.665 | 12100 | 지상 9층 | 레벨 : 지상 9층 | 33900 | 11100 | 33500
7668946 | 지상 9층 | 0.15 | 1.665 | 11850 | 지상 9층 | 레벨 : 지상 9층 | 33900 | 11100 | 33500
7669003 | 지상 10층 | 0.15 | 1.665 | 12100 | 지상 10층 | 레벨 : 지상 10층 | 38400 | 11100 | 38000
7669004 | 지상 10층 | 0.15 | 1.665 | 11850 | 지상 10층 | 레벨 : 지상 10층 | 38400 | 11100 | 38000

# IfcBeam: BM111-철근콘크리트구조 보:BM110-철근 콘크리트구조 보_600 x 500_RG12 (2)
In: 옥탑층
Type - ID 데이터 - 유형 마크: G12; 유형 이름: BM110-철근 콘크리트구조 보_600 x 500_RG12
Type - 구조 - 단면 모양: 0
Type - 기타 - 내화구조여부: yes; 주요구조부여부: yes; 카테고리: 구조 프레임; KBIMS-부위코드: E23; 제작정보: bSK-2021_KBIMS2.0-bC; 조달청표준공사코드: AD; 패밀리 이름: BM111-철근콘크리트구조 보
Type - 재료 및 마감재 - 구조 재료: KBIMS-콘크리트
Type - 치수 - 가로치수: 600 mm; 세로치수: 500 mm
Type - Pset_BeamCommon - IsExternal: no; LoadBearing: yes
Material: KBIMS-콘크리트
Pset_BeamCommon - Slope: 0 deg; Reference: BM110-철근 콘크리트구조 보_600 x 500_RG12
Pset_QuantityTakeOff - Reference: BM110-철근 콘크리트구조 보_600 x 500_RG12; sets with these values: 2
ID 데이터 - 연관 있음: no
공정 - 생성 공정: 새 구성
구속조건 - 끝 레벨 간격띄우기: 0 mm; 단면형상 회전: 0 deg; 방향: 보통; 시작 레벨 간격띄우기: 0 mm; 참조 레벨: 옥탑층; 작업 기준면: 레벨 : 옥탑층; 참조 레벨 입면도: 43400 mm
구조 - 보강 철근 피복 - 다른 면: 보강 철근 피복 1 <25 mm>; 보강 철근 피복 - 하단 면: 보강 철근 피복 1 <25 mm>; 시작 부착 유형: 끝 입면; 구조적 용도: 거더; 끝 부착 유형: 끝 입면
기타 - 패밀리: BM111-철근콘크리트구조 보; 유형: BM110-철근 콘크리트구조 보_600 x 500_RG12; 유형 ID: 7669448; 패밀리 및 유형: BM111-철근콘크리트구조 보: BM110-철근 콘크리트구조 보_600 x 500_RG12
기하학적 위치 - yz 맞춤: 균일; y 간격띄우기 값: 0 mm; y 맞춤: 원점; z 간격띄우기 값: 0 mm; z 맞춤: 상단; 결합 상태: 두 결합 모두 사용
치수 - 단면적: 0.3 m2; 상단 기준 레벨: 43400 mm; 하단 기준 레벨: 42900 mm
Name (BM111-철근콘크리트구조 보:BM110-철근 콘크리트구조 보_600 x 500_RG12:...) | CrossSectionArea (m2) | NetVolume (m3) = 체적 (m3) | Span (mm) = 길이 (mm) | 절단 길이 (mm)
7669069 | 13.275 | 2.5675 | 12100 | 12500 | 구조 - 보강 철근 피복 - 상단 면: 보강 철근 피복 1 <25 mm>
7669070 | 0.21 | 2.331 | 11850 | 11100

# IfcBeam: BM111-철근콘크리트구조 보:BM110-철근 콘크리트구조 보_600 x 600_RAWG1 (8)
Type - PredefinedType: BEAM; Material: KBIMS-콘크리트 (2)
Type - ID 데이터 - 유형 마크: WG1; 유형 이름: BM110-철근 콘크리트구조 보_600 x 600_RAWG1
Type - 구조 - 단면 모양: 0
Type - 기타 - 내화구조여부: yes; 주요구조부여부: yes; 카테고리: 구조 프레임; KBIMS-부위코드: E23; 제작정보: bSK-2021_KBIMS2.0-bC; 조달청표준공사코드: AD; 패밀리 이름: BM111-철근콘크리트구조 보
Type - 재료 및 마감재 - 구조 재료: KBIMS-콘크리트
Type - 치수 - 가로치수: 600 mm; 세로치수: 600 mm
Type - Pset_BeamCommon - IsExternal: no; LoadBearing: yes
Pset_BeamCommon - Reference: BM110-철근 콘크리트구조 보_600 x 600_RAWG1
Pset_QuantityTakeOff - Reference: BM110-철근 콘크리트구조 보_600 x 600_RAWG1; sets with these values: 2
ID 데이터 - 연관 있음: no
공정 - 생성 공정: 새 구성
구속조건 - 단면형상 회전: 0 deg
구조 - 보강 철근 피복 - 다른 면: 보강 철근 피복 1 <25 mm>; 구조적 용도: 기타
기타 - 패밀리: BM111-철근콘크리트구조 보; 유형: BM110-철근 콘크리트구조 보_600 x 600_RAWG1; 유형 ID: 7669397; 패밀리 및 유형: BM111-철근콘크리트구조 보: BM110-철근 콘크리트구조 보_600 x 600_RAWG1
기하학적 위치 - yz 맞춤: 균일; y 간격띄우기 값: 0 mm; y 맞춤: 원점; z 간격띄우기 값: 0 mm; z 맞춤: 상단; 결합 상태: 두 결합 모두 사용
치수 - 단면적: 0.36 m2
Name (BM111-철근콘크리트구조 보:BM110-철근 콘크리트구조 보_600 x 600_RAWG1:...) | In | Span (mm) = 길이 (mm) | Slope (deg) | CrossSectionArea (m2) | NetVolume (m3) = 체적 (m3) | 참조 레벨 | 참조 레벨 입면도 (mm) | 끝 레벨 간격띄우기 (mm) | 시작 레벨 간격띄우기 (mm) | 절단 길이 (mm) | Material
7669267 | 지상 1층 | 15857 | 9.25238 | 8.47312 | 1.05408 | 지상 1층 | 0 | -2150.45 | -4700 | 15663.8 | BaseQuantities - NetSurfaceArea: 16.9462 m2; 구조 - 시작 부착 유형: 끝 입면
7669277 | 지하1층 | 18532 | 4.48758 | 10.8843 | 1.14529 | 지하1층 | -6100 | 1450 | 0 | 18528.8 | KBIMS-콘크리트 | 구조 - 보강 철근 피복 - 하단 면: 보강 철근 피복 1 <25 mm>
7669278 | 지하1층 | 9294 | 8.97565 | 6.80797 | 1.15008 | 지하1층 | -6100 | 0 | 1450 | 9319.98 | KBIMS-콘크리트
7669279 | 지상 1층 | 15857 | 9.25238 | 16.1805 | 3.54313 | 지상 1층 | 0 | -2150.45 | -4700 | 15882.4 | BaseQuantities - NetSurfaceArea: 32.3609 m2
7669280 | 지하1층 | 11213 | 9.75637 | 0.00452926 | 0.721813 | 지하1층 | -6100 | 0 | -1900 | 11061.7 | BaseQuantities - NetSurfaceArea: 13.2843 m2; Length: 3308.09 mm; OuterSurfaceArea: 1.47308 m2; GrossSurfaceArea: 1.48214 m2; GrossVolume: 0.0149832 m3; 구조 - 시작 부착 유형: 끝 입면; 끝 부착 유형: 끝 입면
7669281 | 지하1층 | 10599 | 9.77778 | 10.8641 | 1.88438 | 지하1층 | -6100 | 0 | -1800 | 10561.1 | KBIMS-콘크리트 | 구조 - 끝 부착 유형: 끝 입면
7669282 | 지하2층 | 4782 | 12.0416 | 5.11585 | 0.522536 | 지하2층 | -10100 | 1202.37 | 2200 | 4807.72 | KBIMS-콘크리트
7669283 | 지하2층 | 18607 | 6.48025 | 8.21643 | 0.602253 | 지하2층 | -10100 | 2100 | 0 | 18619.6 | KBIMS-콘크리트

# IfcBeam: BM111-철근콘크리트구조 보:BM110-철근 콘크리트구조 보_800 x 800_1B7 (2)
In: 지상 1층
Type - ID 데이터 - 유형 마크: B7; 유형 이름: BM110-철근 콘크리트구조 보_800 x 800_1B7
Type - 구조 - 단면 모양: 0
Type - 기타 - 내화구조여부: yes; 주요구조부여부: yes; 카테고리: 구조 프레임; KBIMS-부위코드: E23; 제작정보: bSK-2021_KBIMS2.0-bC; 조달청표준공사코드: AD; 패밀리 이름: BM111-철근콘크리트구조 보
Type - 재료 및 마감재 - 구조 재료: KBIMS-콘크리트
Type - 치수 - 가로치수: 800 mm; 세로치수: 800 mm
Type - Pset_BeamCommon - IsExternal: no; LoadBearing: yes
Material: KBIMS-콘크리트
Pset_BeamCommon - Slope: 0 deg; Reference: BM110-철근 콘크리트구조 보_800 x 800_1B7
Pset_QuantityTakeOff - Reference: BM110-철근 콘크리트구조 보_800 x 800_1B7; sets with these values: 2
ID 데이터 - 연관 있음: no
공정 - 생성 공정: 새 구성
구속조건 - 끝 레벨 간격띄우기: 0 mm; 단면형상 회전: 0 deg; 방향: 보통; 시작 레벨 간격띄우기: 0 mm; 참조 레벨: 지상 1층; 참조 레벨 입면도: 0 mm; 작업 기준면: 레벨 : 지상 1층
구조 - 보강 철근 피복 - 다른 면: 보강 철근 피복 1 <25 mm>; 보강 철근 피복 - 하단 면: 보강 철근 피복 1 <25 mm>; 구조적 용도: 기타
기타 - 패밀리: BM111-철근콘크리트구조 보; 유형: BM110-철근 콘크리트구조 보_800 x 800_1B7; 유형 ID: 7667215; 패밀리 및 유형: BM111-철근콘크리트구조 보: BM110-철근 콘크리트구조 보_800 x 800_1B7
기하학적 위치 - yz 맞춤: 균일; y 간격띄우기 값: 0 mm; y 맞춤: 원점; z 맞춤: 상단; 결합 상태: 두 결합 모두 사용; z 간격띄우기 값: -600 mm
치수 - 단면적: 0.64 m2; 상단 기준 레벨: -600 mm; 하단 기준 레벨: -1400 mm
Name (BM111-철근콘크리트구조 보:BM110-철근 콘크리트구조 보_800 x 800_1B7:...) | CrossSectionArea (m2) | NetVolume (m3) = 체적 (m3) | Span (mm) = 길이 (mm) | 절단 길이 (mm)
7667186 | 7.9218 | 2.3417 | 5800 | 5800
7668331 | 0.14605 | 0.00202495 | 5900 | 13.8648

# IfcBeam: BM114-꺾임 보:BM114-꺾임 보_400x600_1WG2, BM114-꺾임 보:BM114-꺾임 보_400x600_1WG2:7669304
In: 지상 1층
Type - PredefinedType: BEAM; Material: Concrete Beam (G40) (2)
Type - ID 데이터 - 유형 마크: WG2; 유형 이름: BM114-꺾임 보_400x600_1WG2
Type - 구조 - 단면 모양: 0
Type - 기타 - 내화구조여부: yes; 주요구조부여부: yes; 카테고리: 구조 프레임; KBIMS-부위코드: E23; 제작정보: bSK-2021_KBIMS2.0-bC; 조달청표준공사코드: AD; 패밀리 이름: BM114-꺾임 보
Type - 치수 - 가로치수: 400 mm; 세로치수: 600 mm
Type - Pset_BeamCommon - IsExternal: no; LoadBearing: yes
Pset_BeamCommon - Slope: 0 deg; Reference: BM114-꺾임 보_400x600_1WG2; Span: 10701.8 mm
Pset_QuantityTakeOff - Reference: BM114-꺾임 보_400x600_1WG2; sets with these values: 2
BaseQuantities - Length: 2524.72 mm; CrossSectionArea: 0.0455458 m2; OuterSurfaceArea: 2.59473 m2; GrossSurfaceArea: 2.68582 m2; GrossVolume: 0.11499 m3; NetVolume: 0.190446 m3; NetSurfaceArea: 4.47365 m2
ID 데이터 - 연관 있음: no
공정 - 생성 공정: 새 구성
구속조건 - 끝 레벨 간격띄우기: 0 mm; 단면형상 회전: 0 deg; 방향: 보통; 시작 레벨 간격띄우기: 0 mm; 참조 레벨: 지상 1층; 참조 레벨 입면도: 0 mm; 작업 기준면: 레벨 : 지상 1층
구조 - 보강 철근 피복 - 다른 면: 보강 철근 피복 1 <25 mm>; 보강 철근 피복 - 하단 면: 보강 철근 피복 1 <25 mm>; 구조적 용도: 기타; 절단 길이: 4424.71 mm
기타 - 유형: BM114-꺾임 보_400x600_1WG2; 유형 ID: 7647207; 패밀리: BM114-꺾임 보; 패밀리 및 유형: BM114-꺾임 보: BM114-꺾임 보_400x600_1WG2
기하학적 위치 - yz 맞춤: 균일; y 간격띄우기 값: 0 mm; y 맞춤: 원점; z 간격띄우기 값: 0 mm; z 맞춤: 상단; 결합 상태: 두 결합 모두 사용
재료 및 마감재 - 구조 재료: KBIMS_콘크리트
치수 - 상단 기준 레벨: 0 mm; 길이: 10701.8 mm; 꺽임 깊이: 600 mm; 꺽임 폭: 7900 mm; 단면적: 0.24 m2; 체적: 0.190446 m3; 하단 기준 레벨: -1200 mm

# IfcBeam: BM114-꺾임 보:BM114-꺾임 보_400x600_1WG2, BM114-꺾임 보:BM114-꺾임 보_400x600_1WG2:7667200
In: 지상 1층
Type - PredefinedType: BEAM; Material: Concrete Beam (G40) (3)
Type - ID 데이터 - 유형 마크: WG2; 유형 이름: BM114-꺾임 보_400x600_1WG2
Type - 구조 - 단면 모양: 0
Type - 기타 - 내화구조여부: yes; 주요구조부여부: yes; 카테고리: 구조 프레임; KBIMS-부위코드: E23; 제작정보: bSK-2021_KBIMS2.0-bC; 조달청표준공사코드: AD; 패밀리 이름: BM114-꺾임 보
Type - 치수 - 가로치수: 400 mm; 세로치수: 600 mm
Type - Pset_BeamCommon - IsExternal: no; LoadBearing: yes
Pset_BeamCommon - Slope: 0 deg; Reference: BM114-꺾임 보_400x600_1WG2; Span: 10701.8 mm
Pset_QuantityTakeOff - Reference: BM114-꺾임 보_400x600_1WG2; sets with these values: 2
BaseQuantities - CrossSectionArea: 9.48011 m2; NetVolume: 1.8096 m3; NetSurfaceArea: 18.9602 m2
ID 데이터 - 연관 있음: no
공정 - 생성 공정: 새 구성
구속조건 - 끝 레벨 간격띄우기: 0 mm; 단면형상 회전: 0 deg; 방향: 보통; 시작 레벨 간격띄우기: 0 mm; 참조 레벨: 지상 1층; 참조 레벨 입면도: 0 mm; 작업 기준면: 레벨 : 지상 1층
구조 - 보강 철근 피복 - 다른 면: 보강 철근 피복 1 <25 mm>; 보강 철근 피복 - 상단 면: 보강 철근 피복 1 <25 mm>; 보강 철근 피복 - 하단 면: 보강 철근 피복 1 <25 mm>; 구조적 용도: 기타; 절단 길이: 10501.8 mm
기타 - 유형: BM114-꺾임 보_400x600_1WG2; 유형 ID: 7647207; 패밀리: BM114-꺾임 보; 패밀리 및 유형: BM114-꺾임 보: BM114-꺾임 보_400x600_1WG2
기하학적 위치 - yz 맞춤: 균일; y 간격띄우기 값: 0 mm; y 맞춤: 원점; z 간격띄우기 값: 0 mm; z 맞춤: 상단; 결합 상태: 두 결합 모두 사용
재료 및 마감재 - 구조 재료: KBIMS_콘크리트
치수 - 상단 기준 레벨: 0 mm; 길이: 10701.8 mm; 꺽임 깊이: 600 mm; 꺽임 폭: 7900 mm; 단면적: 0.24 m2; 체적: 1.8096 m3; 하단 기준 레벨: -1200 mm

# IfcBeam: BM121-철골구조 보:BM121-철골구조 H형강(H-100x100) 보_H-100x100x8x6_SG11 (103)
In: 옥탑층
Type - ID 데이터 - 유형 마크: SG11; 유형 이름: BM121-철골구조 H형강(H-100x100) 보_H-100x100x8x6_SG11
Type - 구조 - 단면 모양: 0
Type - 기타 - 내화구조여부: yes; 주요구조부여부: yes; 카테고리: 구조 프레임; KBIMS-부위코드: E23; 재료: SS400; 제작정보: bSK-2021_KBIMS2.0-bC; 조달청표준공사코드: AEA; 패밀리 이름: BM121-철골구조 보
Type - 재료 및 마감재 - 구조 재료: KBIMS-철골
Type - 치수 - 곡률반지름: 13 mm; 단면적: 22.4907 m2; 단위무게: 17.6552 m2; 웨브두께: 6 mm; 웨브폭: 100 mm; 플랜지두께: 8 mm; 플랜지폭: 100 mm
Type - Pset_BeamCommon - IsExternal: no; LoadBearing: yes
Material: KBIMS-철골
BaseQuantities - CrossSectionArea: 0.00224916 m2
Pset_BeamCommon - Slope: 0 deg; Reference: BM121-철골구조 H형강(H-100x100) 보_H-100x100x8x6_SG11
Pset_QuantityTakeOff - Reference: BM121-철골구조 H형강(H-100x100) 보_H-100x100x8x6_SG11; sets with these values: 2
ID 데이터 - 연관 있음: no
공정 - 생성 공정: 새 구성
구속조건 - 끝 레벨 간격띄우기: 0 mm; 단면형상 회전: 0 deg; 방향: 보통; 시작 레벨 간격띄우기: 0 mm; 참조 레벨: 지붕층; 작업 기준면: 레벨 : 지붕층; 참조 레벨 입면도: 47400 mm
구조 - 기호 부착 위치: 형상 중심
기타 - 유형: BM121-철골구조 H형강(H-100x100) 보_H-100x100x8x6_SG11; 유형 ID: 7669429; 패밀리: BM121-철골구조 보; 패밀리 및 유형: BM121-철골구조 보: BM121-철골구조 H형강(H-100x100) 보_H-100x100x8x6_SG11
기하학적 위치 - yz 맞춤: 균일; y 간격띄우기 값: 0 mm; y 맞춤: 원점; z 맞춤: 상단; 결합 상태: 두 결합 모두 사용; z 간격띄우기 값: 350 mm
치수 - 상단 기준 레벨: 47750 mm; 하단 기준 레벨: 47650 mm
Name (BM121-철골구조 보:BM121-철골구조 H형강(H-100x100) 보_H-100x100x8x6_SG11:...) | NetVolume (m3) = 체적 (m3) | Span (mm) = 길이 (mm) | 구조적 용도 | 절단 길이 (mm) | 끝 접합 절단 (mm) | 끝 확장 (mm) | 시작 접합 절단 (mm) | 시작 확장 (mm)
7669157 | 0.0103811 | 5460 | 거더 | 4934 | 12.7 | 150 | 12.7 | 150 | 구조 - 시작 부착 유형: 끝 입면; 끝 부착 유형: 끝 입면
7669158 | 0.0103811 | 5460 | 거더 | 4934 | 12.7 | 150 | 12.7 | 150 | 구조 - 시작 부착 유형: 끝 입면; 끝 부착 유형: 끝 입면
7669159 | 0.0103811 | 5509 | 거더 | 4934 | 12.7 | 150 | 12.7 | 150 | 구조 - 시작 부착 유형: 끝 입면; 끝 부착 유형: 끝 입면
7669160 | 0.0103811 | 5460 | 거더 | 4934 | 12.7 | 150 | 12.7 | 150 | 구조 - 시작 부착 유형: 끝 입면; 끝 부착 유형: 끝 입면
7669161 | 0.0103811 | 5460 | 거더 | 4934 | 12.7 | 150 | 12.7 | 150 | 구조 - 시작 부착 유형: 끝 입면; 끝 부착 유형: 끝 입면
7669162 | 0.0096237 | 5100 | 거더 | 4574 | 12.7 | 150 | 12.7 | 150 | 구조 - 시작 부착 유형: 끝 입면; 끝 부착 유형: 끝 입면
7669163 | 0.0094133 | 4919 | 거더 | 4474 | 12.7 | 150 | 12.7 | 150 | 구조 - 시작 부착 유형: 끝 입면; 끝 부착 유형: 끝 입면
7669164 | 0.0094133 | 5000 | 거더 | 4474 | 12.7 | 150 | 12.7 | 150 | 구조 - 시작 부착 유형: 끝 입면; 끝 부착 유형: 끝 입면
7669165 | 0.0094133 | 5000 | 거더 | 4474 | 12.7 | 150 | 12.7 | 150 | 구조 - 시작 부착 유형: 끝 입면; 끝 부착 유형: 끝 입면
7669166 | 0.0094133 | 5000 | 거더 | 4474 | 12.7 | 150 | 12.7 | 150 | 구조 - 시작 부착 유형: 끝 입면; 끝 부착 유형: 끝 입면
7669167 | 0.0094133 | 5000 | 거더 | 4474 | 12.7 | 150 | 12.7 | 150 | 구조 - 시작 부착 유형: 끝 입면; 끝 부착 유형: 끝 입면
7669168 | 0.0096237 | 5100 | 거더 | 4574 | 12.7 | 150 | 12.7 | 150 | 구조 - 시작 부착 유형: 끝 입면; 끝 부착 유형: 끝 입면
7669169 | 0.0106757 | 5600 | 거더 | 5074 | 12.7 | 150 | 12.7 | 150 | 구조 - 시작 부착 유형: 끝 입면; 끝 부착 유형: 끝 입면
7669170 | 0.0106757 | 5600 | 거더 | 5074 | 12.7 | 150 | 12.7 | 150 | 구조 - 시작 부착 유형: 끝 입면; 끝 부착 유형: 끝 입면
7669171 | 0.0106757 | 5600 | 거더 | 5074 | 12.7 | 150 | 12.7 | 150 | 구조 - 시작 부착 유형: 끝 입면; 끝 부착 유형: 끝 입면
7669172 | 0.0106757 | 5600 | 거더 | 5074 | 12.7 | 150 | 12.7 | 150 | 구조 - 시작 부착 유형: 끝 입면; 끝 부착 유형: 끝 입면
7669173 | 0.0106757 | 5600 | 거더 | 5074 | 12.7 | 150 | 12.7 | 150 | 구조 - 시작 부착 유형: 끝 입면; 끝 부착 유형: 끝 입면
7669174 | 0.0110965 | 5868 | 거더 | 5274 | 12.7 | 150 | 12.7 | 150 | 구조 - 시작 부착 유형: 끝 입면; 끝 부착 유형: 끝 입면
7669175 | 0.0078353 | 4250 | 거더 | 3724 | 12.7 | 150 | 12.7 | 150 | 구조 - 시작 부착 유형: 끝 입면; 끝 부착 유형: 끝 입면
7669176 | 0.0078353 | 4250 | 거더 | 3724 | 12.7 | 150 | 12.7 | 150 | 구조 - 시작 부착 유형: 끝 입면; 끝 부착 유형: 끝 입면
7669177 | 0.0120812 | 5868 | 거더 | 5742 | 12.7 | 150 | 12.7 | 150
7669178 | 0.0120812 | 5868 | 거더 | 5742 | 12.7 | 150 | 12.7 | 150
7669179 | 0.0014181 | 1000 | 거더 | 674 | 12.7 | 420.298 | 12.7 | -4770 | 구조 - 끝 부착 유형: 끝 입면
7669180 | 0.000997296 | 800 | 거더 | 474 | 12.7 | 420.298 | 12.7 | -2889.85 | 구조 - 시작 부착 유형: 끝 입면
7669181 | 0.0014181 | 1000 | 거더 | 674 | 12.7 | 420.298 | 12.7 | -4770 | 구조 - 끝 부착 유형: 끝 입면
7669182 | 0.000997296 | 800 | 거더 | 474 | 12.7 | 420.298 | 12.7 | -4770 | 구조 - 시작 부착 유형: 끝 입면
7669183 | 0.0113763 | 5533 | 거더 | 5407 | 12.7 | 150 | 12.7 | 150
7669184 | 0.000997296 | 800 | 거더 | 474 | 12.7 | 420.298 | 12.7 | -4770 | 구조 - 시작 부착 유형: 끝 입면
7669185 | 0.0014181 | 1000 | 거더 | 674 | 12.7 | 420.298 | 12.7 | -4770 | 구조 - 시작 부착 유형: 끝 입면
7669186 | 0.0113763 | 5533 | 거더 | 5407 | 12.7 | 150 | 12.7 | 150
7669187 | 0.011412 | 5600 | 기타 | 5423.96 | 12.7 | 150 |  | -163.036
7669188 | 0.0114121 | 5600 | 기타 | 5424 | 12.7 | 150 |  | -163
7669189 | 0.0011046 | 425 | 기타 | 525 |  | -100 |  | 150
7669190 | 0.0014728 | 600 | 기타 | 700 |  | -100 |  | 150
7669191 | 0.0115173 | 5600 | 기타 | 5474 | 12.7 | 150 | 12.7 | 150
7669192 | 0.0115173 | 5600 | 기타 | 5474 | 12.7 | 150 | 12.7 | 150
7669193 | 0.00102465 | 800 | 기타 | 487 |  | -100 | 12.7 | 150 | 구조 - 시작 부착 유형: 끝 입면
7669194 | 0.00144545 | 1000 | 기타 | 687 |  | -100 | 12.7 | 150 | 구조 - 시작 부착 유형: 끝 입면
7669195 | 0.0012624 | 500 | 기타 | 600 |  | -100 |  | 150
7669196 | 0.0014728 | 600 | 기타 | 700 |  | -100 |  | 150
7669197 | 0.0115173 | 5600 | 기타 | 5474 | 12.7 | 150 | 12.7 | 150
7669198 | 0.0115173 | 5600 | 기타 | 5474 | 12.7 | 150 | 12.7 | 150
7669199 | 0.00986811 | 3701 | 기타 | 4690.17 |  | 1052.17 | 12.7 | 150
7669200 | 0.0133436 | 6468 | 기타 | 6342 | 12.7 | 150 | 12.7 | 150
7669201 | 0.00144545 | 1000 | 기타 | 687 | -0.3 | -100 | 12.7 | 150 | 구조 - 시작 부착 유형: 끝 입면
7669202 | 0.00119503 | 380 | 기타 | 567.982 |  | 37.9823 |  | 150
7669203 | 0.0125975 | 6100 | 기타 | 5987.38 | 12.7 | 150 |  | -99.6161
7669204 | 0.0104921 | 4096 | 기타 | 4986.74 | 12.7 | 150 |  | 953.737
7669205 | 0.00101709 | 796 | 기타 | 483.409 |  | -99.5914 | 12.7 | 150 | 구조 - 시작 부착 유형: 끝 입면
7669206 | 0.00116665 | 867 | 기타 | 554.491 |  | -99.5088 | 12.7 | 150 | 구조 - 시작 부착 유형: 끝 입면
7669207 | 0.0102549 | 5000 | 기타 | 4874 | 12.7 | 150 | 12.7 | 150
7669208 | 0.0102549 | 5000 | 기타 | 4874 | 12.7 | 150 | 12.7 | 150
7669209 | 0.00101709 | 796 | 기타 | 483.409 |  | -99.5914 | 12.7 | 150 | 구조 - 시작 부착 유형: 끝 입면
7669210 | 0.00116665 | 867 | 기타 | 554.491 |  | -99.5088 | 12.7 | 150 | 구조 - 시작 부착 유형: 끝 입면
7669211 | 0.0102549 | 5000 | 기타 | 4874 | 12.7 | 150 | 12.7 | 150
7669212 | 0.0102549 | 5000 | 기타 | 4874 | 12.7 | 150 | 12.7 | 150
7669213 | 0.00101709 | 796 | 기타 | 483.409 |  | -99.5914 | 12.7 | 150 | 구조 - 시작 부착 유형: 끝 입면
7669214 | 0.00116665 | 867 | 기타 | 554.491 |  | -99.5088 | 12.7 | 150 | 구조 - 시작 부착 유형: 끝 입면
7669215 | 0.0102549 | 5000 | 기타 | 4874 | 12.7 | 150 | 12.7 | 150
7669216 | 0.0102549 | 5000 | 기타 | 4874 | 12.7 | 150 | 12.7 | 150
7669217 | 0.00126876 | 503 | 기타 | 603.024 |  | -99.9761 |  | 150
7669218 | 0.00101709 | 796 | 기타 | 483.409 |  | -99.5914 | 12.7 | 150 | 구조 - 시작 부착 유형: 끝 입면
7669219 | 0.0102549 | 5000 | 기타 | 4874 | 12.7 | 150 | 12.7 | 150
7669220 | 0.0102549 | 5000 | 기타 | 4874 | 12.7 | 150 | 12.7 | 150
7669221 | 0.00101709 | 796 | 기타 | 483.409 |  | -99.5914 | 12.7 | 150 | 구조 - 시작 부착 유형: 끝 입면
7669222 | 0.00116665 | 867 | 기타 | 554.491 |  | -99.5088 | 12.7 | 150 | 구조 - 시작 부착 유형: 끝 입면
7669223 | 0.0102549 | 5000 | 기타 | 4874 | 12.7 | 150 | 12.7 | 150
7669224 | 0.0102549 | 5000 | 기타 | 4874 | 12.7 | 150 | 12.7 | 150
7669225 | 0.00101709 | 796 | 기타 | 483.409 |  | -99.5914 | 12.7 | 150 | 구조 - 시작 부착 유형: 끝 입면
7669226 | 0.00116649 | 883 | 기타 | 554.414 |  | -99.5863 | 12.7 | 150 | 구조 - 시작 부착 유형: 끝 입면
7669227 | 0.0104653 | 5100 | 기타 | 4974 | 12.7 | 992.127 | 12.7 | 150
7669228 | 0.0125693 | 6100 | 기타 | 5974 | 12.7 | 150 | 12.7 | 150
7669229 | 0.0014181 | 1000 | 기타 | 674 | 12.7 | -100 | 12.7 | 150 | 구조 - 시작 부착 유형: 끝 입면
7669230 | 0.013049 | 6328 | 기타 | 6202 | 12.7 | 150 | 12.7 | 150
7669231 | 0.00957296 | 3772 | 기타 | 4549.88 |  | 840.885 | 12.7 | 150
7669232 | 0.00116562 | 467 | 기타 | 554 | 12.7 | -99.5088 |  | 150
7669233 | 0.00102493 | 800 | 기타 | 487.133 |  | -99.8668 | 12.7 | 150 | 구조 - 시작 부착 유형: 끝 입면
7669234 | 0.00144545 | 1000 | 기타 | 687 |  | -100 | 12.7 | 150 | 구조 - 시작 부착 유형: 끝 입면
7669235 | 0.00144545 | 1000 | 기타 | 687 |  | -100 | 12.7 | 150 | 구조 - 시작 부착 유형: 끝 입면
7669236 | 0.00102465 | 800 | 기타 | 487 |  | -100 | 12.7 | 150 | 구조 - 시작 부착 유형: 끝 입면
7669237 | 0.0112227 | 5460 | 기타 | 5334 | 12.7 | 150 | 12.7 | 150
7669238 | 0.0112227 | 5460 | 기타 | 5334 | 12.7 | 150 | 12.7 | 150
7669239 | 0.00144545 | 1000 | 기타 | 687 |  | -100 | 12.7 | 150 | 구조 - 시작 부착 유형: 끝 입면
7669240 | 0.00102465 | 800 | 기타 | 487 |  | -100 | 12.7 | 150 | 구조 - 시작 부착 유형: 끝 입면
7669241 | 0.0112227 | 5460 | 기타 | 5334 | 12.7 | 150 | 12.7 | 150
7669242 | 0.0112227 | 5460 | 기타 | 5334 | 12.7 | 150 | 12.7 | 150
7669243 | 0.0112227 | 5460 | 기타 | 5334 | 12.7 | 150 | 12.7 | 150
7669244 | 0.0112227 | 5460 | 기타 | 5334 | 12.7 | 150 | 12.7 | 150
7669245 | 0.00102465 | 800 | 기타 | 487 |  | -100 | 12.7 | 150 | 구조 - 시작 부착 유형: 끝 입면
7669246 | 0.00144588 | 1000 | 기타 | 687.207 |  | -99.7925 | 12.7 | 150 | 구조 - 시작 부착 유형: 끝 입면
7669247 | 0.0016832 | 700 | 기타 | 800 |  | -100 |  | 150
7669248 | 0.0112227 | 5460 | 기타 | 5334 | 12.7 | 150 | 12.7 | 150
7669249 | 0.00985514 | 4810 | 기타 | 4684 | 12.7 | 150 | 12.7 | 374.907
7669250 | 0.000808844 | 284 | 기타 | 384.431 |  | -99.5686 |  | 150
7669251 | 0.00061016 | 203 | 기타 | 290 | 12.7 | 150 |  | 150
7669252 | 0.00870425 | 4250 | 기타 | 4137 | -0.643376 | 150 | 12.7 | 150
7669253 | 0.0086769 | 4250 | 기타 | 4124 | 12.7 | 900.003 | 12.7 | 150
7669254 | 0.00136168 | 547 | 기타 | 647.187 |  | -99.8132 |  | 150
7669255 | 0.0011309 | 650 | 기타 | 537.499 |  | -99.5013 | 12.7 | 150
7669256 | 0.00157684 | 862 | 기타 | 749.45 |  | -99.5501 | 12.7 | 150
7669257 | 0.0014661 | 380 | 기타 | 696.817 |  | 75.0967 |  | 241.721
7669258 | 0.00113104 | 284 | 기타 | 537.569 | 12.7 | -99.5686 |  | 316.569
7669259 | 0.00141178 | 797 | 기타 | 671 | 12.7 | -99.5914 | 12.7 | 150

# IfcBuildingElementProxy: EE112-승강기 리프트카:EE112-승객용 엘리베이터 (13인승) 1600x1350 (2)
Type - Material: KBIMS-스테인리스(운송) (6)
Type - ID 데이터 - OmniClass 번호: 23.75.00.00; OmniClass 제목: Climate Control (HVAC); 유형 이름: EE112-승객용 엘리베이터 (13인승) 1600x1350
Type - 구속조건 - 기본 높이: 0 mm
Type - 기타 - 카테고리: 일반 모델; KBIMS_보급정보-보급코드: bSK-181231; KBIMS_보급정보-저작자: 빌딩스마트협회; KBIMS_식별-버전: 1.02; 패밀리 이름: EE112-승강기 리프트카; 피난용승강기여부: yes
Type - 치수 - 가로: 1600 mm; 높이: 2350 mm; 세로: 1350 mm; 와이어 길이: 44850 mm
Pset_BuildingElementProxyCommon - Reference: EE112-승객용 엘리베이터 (13인승) 1600x1350; sets with these values: 2
Pset_ProvisionForVoid - Width: 1600 mm; Height: 1350 mm; Depth: 2350 mm
공정 - 생성 공정: 새 구성
구속조건 - 레벨: 지상 1층; 가까운 요소로 이동: no; 레벨로부터의 높이: 0 mm; 호스트에서의 간격띄우기: 0 mm; 호스트: 레벨 : 지상 1층
기타 - 유형: EE112-승객용 엘리베이터 (13인승) 1600x1350; 유형 ID: 7472588; 패밀리: EE112-승강기 리프트카; 패밀리 및 유형: EE112-승강기 리프트카: EE112-승객용 엘리베이터 (13인승) 1600x1350
치수 - 면적: 33.7693 m2; 체적: 5.93897 m3
Name (EE112-승강기 리프트카:EE112-승객용 엘리베이터 (13인승) 1600x1350:...) | In
7472688 | 52
7473091 | 53 | Material: KBIMS-스테인리스(운송)

# IfcBuildingElementProxy: PF583-장애인 칸막이:PF583-장애인 칸막이 (20)
Type - Material: <Unnamed> (6), KBIMS-이동식칸막이 (5), KBIMS-스테인리스 스틸_도금 (4)
Type - ID 데이터 - 유형 이름: PF583-장애인 칸막이
Type - 구속조건 - 기본 높이: 0 mm
Type - 그래픽 - 큐비클 다리: yes
Type - 기타 - 카테고리: 가구; KBIMS-부위코드: E714; 제작정보: AIBIM-2023; 조달청표준공사코드: AOC771; 패밀리 이름: PF583-장애인 칸막이
Type - 재료 및 마감재 - 롤러박스 재료: KBIMS-이동식칸막이; 출입문 재료: KBIMS-이동식칸막이; 큐비클다리 재료: KBIMS-스테인리스 스틸_도금; 큐비클 재료: KBIMS-이동식칸막이
Type - 치수 - 높이: 0 mm; 손잡이 높이: 900 mm
Pset_BuildingElementProxyCommon - Reference: PF583-장애인 칸막이; sets with these values: 2
공정 - 생성 공정: 새 구성
구속조건 - 가까운 요소로 이동: no; 호스트에서의 간격띄우기: 0 mm
그래픽 - 큐비클_우: no; 큐비클_좌: no; 손잡이: yes
기타 - 유형: PF583-장애인 칸막이; 유형 ID: 6448293; 패밀리: PF583-장애인 칸막이; 패밀리 및 유형: PF583-장애인 칸막이: PF583-장애인 칸막이
치수 - 깊이: 1430 mm; 깊이_옆판: 1415 mm; 두께: 15 mm; 폭_출입문: 1020 mm; 폭_출입문 장폭: 610 mm; 하단 간격띄우기: 100 mm
Name (PF583-장애인 칸막이:PF583-장애인 칸막이:...) | In | 레벨 | 레벨로부터의 높이 (mm) | 호스트 | 가로 (mm) | 높이 (mm) | 면적 (m2) | 체적 (m3) | 폭_우 (mm) | 폭_좌 (mm) | Material
3146694 | 312 | 지상 10층 | 0 | 레벨 : 지상 10층 | 2380 | 2400 | 12.2841 | 0.170685 | 200 | 1160
3146695 | 313 | 지상 10층 | 0 | 레벨 : 지상 10층 | 2540.02 | 2400 | 12.6545 | 0.176206 | 1000.02 | 520
6568313 | 171 | 지상 1층 | -510 | 바닥 : A1-14-03A-시멘트모르타르(고름용), 도막방수, 시멘트모르타르(보호용), 자기질타일 (90mm) | 2540.02 | 1900 | 9.92799 | 0.137966 | 1000.02 | 520
6568334 | 189 | 지상 2층 | 0 | 레벨 : 지상 2층 | 2540.02 | 2400 | 12.6545 | 0.176206 | 1000.02 | 520 | <Unnamed>, KBIMS-이동식칸막이, KBIMS-스테인리스 스틸_도금
6568355 | 203 | 지상 3층 | 0 | 레벨 : 지상 3층 | 2540.02 | 2400 | 12.6545 | 0.176206 | 1000.02 | 520 | <Unnamed>, KBIMS-이동식칸막이, KBIMS-스테인리스 스틸_도금
6568376 | 221 | 지상 4층 | 0 | 레벨 : 지상 4층 | 2540.02 | 2400 | 12.6545 | 0.176206 | 1000.02 | 520 | <Unnamed>, KBIMS-이동식칸막이, KBIMS-스테인리스 스틸_도금
6568397 | 226 | 지상 5층 | 0 | 레벨 : 지상 5층 | 2540.02 | 2400 | 12.6545 | 0.176206 | 1000.02 | 520 | <Unnamed>, KBIMS-이동식칸막이, KBIMS-스테인리스 스틸_도금
6568418 | 241 | 지상 6층 | 0 | 레벨 : 지상 6층 | 2540.02 | 2400 | 12.6545 | 0.176206 | 1000.02 | 520 | <Unnamed>, KBIMS-이동식칸막이, KBIMS-스테인리스 스틸_도금
6568439 | 267 | 지상 7층 | 0 | 레벨 : 지상 7층 | 2540.02 | 2400 | 12.6545 | 0.176206 | 1000.02 | 520 | <Unnamed>, KBIMS-이동식칸막이, KBIMS-스테인리스 스틸_도금
6568460 | 279 | 지상 8층 | 0 | 레벨 : 지상 8층 | 2540.02 | 2400 | 12.6545 | 0.176206 | 1000.02 | 520 | <Unnamed>, KBIMS-이동식칸막이, KBIMS-스테인리스 스틸_도금
6568481 | 298 | 지상 9층 | 0 | 레벨 : 지상 9층 | 2540.02 | 2400 | 12.6545 | 0.176206 | 1000.02 | 520 | <Unnamed>, KBIMS-이동식칸막이, KBIMS-스테인리스 스틸_도금
6569378 | 170 | 지상 1층 | -510 | 바닥 : A1-14-03A-시멘트모르타르(고름용), 도막방수, 시멘트모르타르(보호용), 자기질타일 (90mm) | 2380 | 1900 | 9.63756 | 0.133645 | 200 | 1160
6569399 | 188 | 지상 2층 | 0 | 레벨 : 지상 2층 | 2380 | 2400 | 12.2841 | 0.170685 | 200 | 1160 | <Unnamed>, KBIMS-이동식칸막이, KBIMS-스테인리스 스틸_도금
6569420 | 202 | 지상 3층 | 0 | 레벨 : 지상 3층 | 2380 | 2400 | 12.2841 | 0.170685 | 200 | 1160 | <Unnamed>, KBIMS-이동식칸막이, KBIMS-스테인리스 스틸_도금
6569441 | 222 | 지상 4층 | 0 | 레벨 : 지상 4층 | 2380 | 2400 | 12.2841 | 0.170685 | 200 | 1160 | <Unnamed>, KBIMS-이동식칸막이, KBIMS-스테인리스 스틸_도금
6569462 | 225 | 지상 5층 | 0 | 레벨 : 지상 5층 | 2380 | 2400 | 12.2841 | 0.170685 | 200 | 1160 | <Unnamed>, KBIMS-이동식칸막이, KBIMS-스테인리스 스틸_도금
6569483 | 240 | 지상 6층 | 0 | 레벨 : 지상 6층 | 2380 | 2400 | 12.2841 | 0.170685 | 200 | 1160 | <Unnamed>, KBIMS-이동식칸막이, KBIMS-스테인리스 스틸_도금
6569504 | 266 | 지상 7층 | 0 | 레벨 : 지상 7층 | 2380 | 2400 | 12.2841 | 0.170685 | 200 | 1160 | <Unnamed>, KBIMS-이동식칸막이, KBIMS-스테인리스 스틸_도금
6569525 | 278 | 지상 8층 | 0 | 레벨 : 지상 8층 | 2380 | 2400 | 12.2841 | 0.170685 | 200 | 1160 | <Unnamed>, KBIMS-이동식칸막이, KBIMS-스테인리스 스틸_도금
6569546 | 297 | 지상 9층 | 0 | 레벨 : 지상 9층 | 2380 | 2400 | 12.2841 | 0.170685 | 200 | 1160 | <Unnamed>, KBIMS-이동식칸막이, KBIMS-스테인리스 스틸_도금

# IfcBuildingElementProxy: SE251-기본주차:SE251-기본주차 경형 (13)
Type - Material: KBIMS-고무_검은색 (2), KBIMS-에폭시 페인트
Type - ID 데이터 - 설명: 기본주차 경형; 유형 이름: SE251-기본주차 경형
Type - 구속조건 - 기본 높이: 0 mm
Type - 그래픽 - 여성전용: no; 카스토퍼: yes; 장애인주차 표시: no
Type - 기타 - 카테고리: 주차장; KBIMS-부위코드: E77; 제작정보: bSK-2021_KBIMS2.0-bC; 조달청표준공사코드: CLH2601; 패밀리 이름: SE251-기본주차
Type - 재료 및 마감재 - 보행안전통로 표시선 재료: KBIMS-노면용 페인트_노란색; 여성전용마크 재료: KBIMS-노면용 페인트_분홍색; 장애인마크 재료: KBIMS-노면용 페인트_흰색; 주차표면_일반: KBIMS-에폭시 페인트; 주차표면_장애인용: KBIMS-노면용 페인트_진하늘색
Type - 치수 - 길이: 3600 mm; 마크 두께: 1 mm; 보행안전통로 폭: 1000 mm; 보행안전통로 표시선 두께: 200 mm; 카스토퍼 이격거리(세로): 1100 mm; 폭: 2000 mm
Pset_BuildingElementProxyCommon - Reference: SE251-기본주차 경형; sets with these values: 2
Pset_ProvisionForVoid - Depth: 1.6 mm
공정 - 생성 공정: 새 구성
구속조건 - 가까운 요소로 이동: no; 호스트에서의 간격띄우기: 100 mm
그래픽 - 원점: no
기타 - 패밀리: SE251-기본주차; 유형: SE251-기본주차 경형; 유형 ID: 3098912; 주차단위구획: 경형; 주차형식: 직각주차; 패밀리 및 유형: SE251-기본주차: SE251-기본주차 경형
치수 - 면적: 22.2704 m2; 체적: 0.0518365 m3
Name (SE251-기본주차:SE251-기본주차 경형:...) | In | Width (mm) | Height (mm) | 레벨 | 호스트 | Material
3098513 | 125 | 2000 | 3600 | 지하2층 | 레벨 : 지하2층
3098516 | 125 | 2000 | 3600 | 지하2층 | 레벨 : 지하2층 | KBIMS-고무_검은색, KBIMS-에폭시 페인트
3098517 | 125 | 2000 | 3600 | 지하2층 | 레벨 : 지하2층 | KBIMS-고무_검은색, KBIMS-에폭시 페인트
3098518 | 125 | 2000 | 3600 | 지하2층 | 레벨 : 지하2층 | KBIMS-고무_검은색, KBIMS-에폭시 페인트
3098521 | 125 | 3600 | 2000 | 지하2층 | 레벨 : 지하2층
3107479 | 136 | 2000 | 3600 | 지하1층 | 레벨 : 지하1층 | KBIMS-고무_검은색, KBIMS-에폭시 페인트
3107481 | 136 | 2000 | 3600 | 지하1층 | 레벨 : 지하1층 | KBIMS-고무_검은색, KBIMS-에폭시 페인트
3107488 | 136 | 3600 | 2000 | 지하1층 | 레벨 : 지하1층 | KBIMS-고무_검은색, KBIMS-에폭시 페인트
3107489 | 136 | 3600 | 2000 | 지하1층 | 레벨 : 지하1층 | KBIMS-고무_검은색, KBIMS-에폭시 페인트
3107490 | 136 | 3600 | 2000 | 지하1층 | 레벨 : 지하1층 | KBIMS-고무_검은색, KBIMS-에폭시 페인트
3107491 | 136 | 3600 | 2000 | 지하1층 | 레벨 : 지하1층 | KBIMS-고무_검은색, KBIMS-에폭시 페인트
3107495 | 136 | 2000 | 3600 | 지하1층 | 레벨 : 지하1층 | KBIMS-고무_검은색, KBIMS-에폭시 페인트
3107497 | 136 | 2000 | 3600 | 지하1층 | 레벨 : 지하1층 | KBIMS-고무_검은색, KBIMS-에폭시 페인트

# IfcBuildingElementProxy: SE251-기본주차:SE251-기본주차 여성전용일반형 (8)
In: 136
Type - Material: KBIMS-노면용 페인트_분홍색 (2), KBIMS-고무_검은색 (2), KBIMS-에폭시 페인트
Type - ID 데이터 - 설명: 기본주차 여성전용일반형; 유형 이름: SE251-기본주차 여성전용일반형
Type - 구속조건 - 기본 높이: 0 mm
Type - 그래픽 - 카스토퍼: yes; 장애인주차 표시: no; 여성전용: yes
Type - 기타 - 카테고리: 주차장; KBIMS-부위코드: E77; 제작정보: bSK-2021_KBIMS2.0-bC; 조달청표준공사코드: CLH2601; 패밀리 이름: SE251-기본주차
Type - 재료 및 마감재 - 보행안전통로 표시선 재료: KBIMS-노면용 페인트_노란색; 여성전용마크 재료: KBIMS-노면용 페인트_분홍색; 장애인마크 재료: KBIMS-노면용 페인트_흰색; 주차표면_일반: KBIMS-에폭시 페인트; 주차표면_장애인용: KBIMS-노면용 페인트_진하늘색
Type - 치수 - 길이: 5000 mm; 마크 두께: 1 mm; 보행안전통로 폭: 1000 mm; 보행안전통로 표시선 두께: 200 mm; 카스토퍼 이격거리(세로): 1100 mm; 폭: 2500 mm
Pset_BuildingElementProxyCommon - Reference: SE251-기본주차 여성전용일반형; sets with these values: 2
Pset_ProvisionForVoid - Width: 2500 mm; Height: 5000 mm; Depth: 1.6 mm
공정 - 생성 공정: 새 구성
구속조건 - 레벨: 지하1층; 가까운 요소로 이동: no; 호스트: 레벨 : 지하1층; 호스트에서의 간격띄우기: 100 mm
그래픽 - 원점: no
기타 - 패밀리: SE251-기본주차; 유형: SE251-기본주차 여성전용일반형; 유형 ID: 3107502; 주차단위구획: 일반형; 주차형식: 직각주차; 패밀리 및 유형: SE251-기본주차: SE251-기본주차 여성전용일반형
치수 - 면적: 34.5646 m2; 체적: 0.0633993 m3
Name (SE251-기본주차:SE251-기본주차 여성전용일반형:...) | Material
3107463
3107464 | KBIMS-노면용 페인트_분홍색, KBIMS-고무_검은색, KBIMS-에폭시 페인트
3107465 | KBIMS-노면용 페인트_분홍색, KBIMS-고무_검은색, KBIMS-에폭시 페인트
3107466 | KBIMS-노면용 페인트_분홍색, KBIMS-고무_검은색, KBIMS-에폭시 페인트
3107467 | KBIMS-노면용 페인트_분홍색, KBIMS-고무_검은색, KBIMS-에폭시 페인트
3107468 | KBIMS-노면용 페인트_분홍색, KBIMS-고무_검은색, KBIMS-에폭시 페인트
3107469 | KBIMS-노면용 페인트_분홍색, KBIMS-고무_검은색, KBIMS-에폭시 페인트
3107470 | KBIMS-노면용 페인트_분홍색, KBIMS-고무_검은색, KBIMS-에폭시 페인트

# IfcBuildingElementProxy: SE251-기본주차:SE251-기본주차 일반형 (23)
Type - Material: KBIMS-고무_검은색 (2), KBIMS-에폭시 페인트
Type - ID 데이터 - 설명: 기본주차 일반형; 유형 이름: SE251-기본주차 일반형
Type - 구속조건 - 기본 높이: 0 mm
Type - 그래픽 - 여성전용: no; 카스토퍼: yes; 장애인주차 표시: no
Type - 기타 - 카테고리: 주차장; KBIMS-부위코드: E77; 제작정보: bSK-2021_KBIMS2.0-bC; 조달청표준공사코드: CLH2601; 패밀리 이름: SE251-기본주차
Type - 재료 및 마감재 - 보행안전통로 표시선 재료: KBIMS-노면용 페인트_노란색; 여성전용마크 재료: KBIMS-노면용 페인트_분홍색; 장애인마크 재료: KBIMS-노면용 페인트_흰색; 주차표면_일반: KBIMS-에폭시 페인트; 주차표면_장애인용: KBIMS-노면용 페인트_진하늘색
Type - 치수 - 길이: 5000 mm; 마크 두께: 1 mm; 보행안전통로 폭: 1000 mm; 보행안전통로 표시선 두께: 200 mm; 카스토퍼 이격거리(세로): 1100 mm; 폭: 2500 mm
Pset_BuildingElementProxyCommon - Reference: SE251-기본주차 일반형; sets with these values: 2
Pset_ProvisionForVoid - Depth: 1.6 mm
공정 - 생성 공정: 새 구성
구속조건 - 가까운 요소로 이동: no; 호스트에서의 간격띄우기: 100 mm
그래픽 - 원점: no
기타 - 패밀리: SE251-기본주차; 유형: SE251-기본주차 일반형; 유형 ID: 3098914; 주차단위구획: 일반형; 주차형식: 직각주차; 패밀리 및 유형: SE251-기본주차: SE251-기본주차 일반형
치수 - 면적: 34.5646 m2; 체적: 0.0633993 m3
Name (SE251-기본주차:SE251-기본주차 일반형:...) | In | Width (mm) | Height (mm) | 레벨 | 호스트 | Material
3098502 | 125 | 2500 | 5000 | 지하2층 | 레벨 : 지하2층
3098514 | 125 | 2500 | 5000 | 지하2층 | 레벨 : 지하2층 | KBIMS-고무_검은색, KBIMS-에폭시 페인트
3098515 | 125 | 2500 | 5000 | 지하2층 | 레벨 : 지하2층 | KBIMS-고무_검은색, KBIMS-에폭시 페인트
3098519 | 125 | 5000 | 2500 | 지하2층 | 레벨 : 지하2층
3098520 | 125 | 5000 | 2500 | 지하2층 | 레벨 : 지하2층 | KBIMS-고무_검은색, KBIMS-에폭시 페인트
3098522 | 125 | 5000 | 2500 | 지하2층 | 레벨 : 지하2층 | KBIMS-고무_검은색, KBIMS-에폭시 페인트
3098523 | 125 | 5000 | 2500 | 지하2층 | 레벨 : 지하2층 | KBIMS-고무_검은색, KBIMS-에폭시 페인트
3107471 | 136 | 2500 | 5000 | 지하1층 | 레벨 : 지하1층 | KBIMS-고무_검은색, KBIMS-에폭시 페인트
3107472 | 136 | 2500 | 5000 | 지하1층 | 레벨 : 지하1층 | KBIMS-고무_검은색, KBIMS-에폭시 페인트
3107476 | 136 | 2500 | 5000 | 지하1층 | 레벨 : 지하1층 | KBIMS-고무_검은색, KBIMS-에폭시 페인트
3107477 | 136 | 2500 | 5000 | 지하1층 | 레벨 : 지하1층 | KBIMS-고무_검은색, KBIMS-에폭시 페인트
3107478 | 136 | 2500 | 5000 | 지하1층 | 레벨 : 지하1층 | KBIMS-고무_검은색, KBIMS-에폭시 페인트
3107480 | 136 | 2500 | 5000 | 지하1층 | 레벨 : 지하1층 | KBIMS-고무_검은색, KBIMS-에폭시 페인트
3107482 | 136 | 5000 | 2500 | 지하1층 | 레벨 : 지하1층 | KBIMS-고무_검은색, KBIMS-에폭시 페인트
3107483 | 136 | 2500 | 5000 | 지하1층 | 레벨 : 지하1층 | KBIMS-고무_검은색, KBIMS-에폭시 페인트
3107484 | 136 | 2500 | 5000 | 지하1층 | 레벨 : 지하1층 | KBIMS-고무_검은색, KBIMS-에폭시 페인트
3107485 | 136 | 2500 | 5000 | 지하1층 | 레벨 : 지하1층 | KBIMS-고무_검은색, KBIMS-에폭시 페인트
3107486 | 136 | 2500 | 5000 | 지하1층 | 레벨 : 지하1층 | KBIMS-고무_검은색, KBIMS-에폭시 페인트
3107487 | 136 | 2500 | 5000 | 지하1층 | 레벨 : 지하1층 | KBIMS-고무_검은색, KBIMS-에폭시 페인트
3107494 | 136 | 2500 | 5000 | 지하1층 | 레벨 : 지하1층 | KBIMS-고무_검은색, KBIMS-에폭시 페인트
3107496 | 136 | 5000 | 2500 | 지하1층 | 레벨 : 지하1층 | KBIMS-고무_검은색, KBIMS-에폭시 페인트
3107498 | 136 | 5000 | 2500 | 지하1층 | 레벨 : 지하1층 | KBIMS-고무_검은색, KBIMS-에폭시 페인트
3107499 | 136 | 5000 | 2500 | 지하1층 | 레벨 : 지하1층 | KBIMS-고무_검은색, KBIMS-에폭시 페인트

# IfcBuildingElementProxy: SE251-기본주차:SE251-기본주차 장애인전용 (5)
Type - Material: KBIMS-노면용 페인트_흰색 (5), KBIMS-페인트_검은색, KBIMS-페인트_흰색 (30), KBIMS-페인트_파란색, <Unnamed>, KBIMS-스테인리스 스틸_도금, KBIMS-노면용 페인트_노란색 (4), KBIMS-노면용 페인트_진하늘색 (2), KBIMS-고무_검은색 (2), KBIMS-에폭시 페인트
Type - ID 데이터 - 설명: 기본주차 장애인전용; 유형 이름: SE251-기본주차 장애인전용
Type - 구속조건 - 기본 높이: 0 mm
Type - 그래픽 - 여성전용: no; 장애인주차 표시: yes; 카스토퍼: yes
Type - 기타 - 카테고리: 주차장; KBIMS-부위코드: E77; 제작정보: bSK-2021_KBIMS2.0-bC; 조달청표준공사코드: CLH2601; 패밀리 이름: SE251-기본주차
Type - 재료 및 마감재 - 보행안전통로 표시선 재료: KBIMS-노면용 페인트_노란색; 여성전용마크 재료: KBIMS-노면용 페인트_분홍색; 장애인마크 재료: KBIMS-노면용 페인트_흰색; 주차표면_일반: KBIMS-에폭시 페인트; 주차표면_장애인용: KBIMS-노면용 페인트_진하늘색
Type - 치수 - 길이: 5000 mm; 마크 두께: 1 mm; 보행안전통로 폭: 1000 mm; 보행안전통로 표시선 두께: 200 mm; 카스토퍼 이격거리(세로): 1100 mm; 폭: 2300 mm
Pset_BuildingElementProxyCommon - Reference: SE251-기본주차 장애인전용; sets with these values: 2
공정 - 생성 공정: 새 구성
구속조건 - 가까운 요소로 이동: no; 호스트에서의 간격띄우기: 100 mm
그래픽 - 원점: no
기타 - 유형: SE251-기본주차 장애인전용; 유형 ID: 3098911; 주차단위구획: 장애인전용; 주차형식: 직각주차; 패밀리: SE251-기본주차; 패밀리 및 유형: SE251-기본주차: SE251-기본주차 장애인전용
치수 - 면적: 32.5639 m2; 체적: 0.0853593 m3
Name (SE251-기본주차:SE251-기본주차 장애인전용:...) | In | 레벨 | 호스트 | Material
3098501 | 125 | 지하2층 | 레벨 : 지하2층
3098505 | 125 | 지하2층 | 레벨 : 지하2층 | KBIMS-노면용 페인트_흰색, KBIMS-페인트_검은색, KBIMS-페인트_흰색, KBIMS-페인트_파란색, <Unnamed>, KBIMS-스테인리스 스틸_도금, KBIMS-노면용 페인트_노란색, KBIMS-노면용 페인트_진하늘색, KBIMS-고무_검은색, KBIMS-에폭시 페인트
3107473 | 136 | 지하1층 | 레벨 : 지하1층 | KBIMS-노면용 페인트_흰색, KBIMS-페인트_검은색, KBIMS-페인트_흰색, KBIMS-페인트_파란색, <Unnamed>, KBIMS-스테인리스 스틸_도금, KBIMS-노면용 페인트_노란색, KBIMS-노면용 페인트_진하늘색, KBIMS-고무_검은색, KBIMS-에폭시 페인트
3107474 | 136 | 지하1층 | 레벨 : 지하1층 | KBIMS-노면용 페인트_흰색, KBIMS-페인트_검은색, KBIMS-페인트_흰색, KBIMS-페인트_파란색, <Unnamed>, KBIMS-스테인리스 스틸_도금, KBIMS-노면용 페인트_노란색, KBIMS-노면용 페인트_진하늘색, KBIMS-고무_검은색, KBIMS-에폭시 페인트
3107475 | 136 | 지하1층 | 레벨 : 지하1층 | KBIMS-노면용 페인트_흰색, KBIMS-페인트_검은색, KBIMS-페인트_흰색, KBIMS-페인트_파란색, <Unnamed>, KBIMS-스테인리스 스틸_도금, KBIMS-노면용 페인트_노란색, KBIMS-노면용 페인트_진하늘색, KBIMS-고무_검은색, KBIMS-에폭시 페인트

# IfcBuildingElementProxy: SE251-기본주차:SE251-기본주차 확장형 (11)
Type - Material: KBIMS-고무_검은색 (2), KBIMS-에폭시 페인트
Type - ID 데이터 - 설명: 기본주차 확장형; 유형 이름: SE251-기본주차 확장형
Type - 구속조건 - 기본 높이: 0 mm
Type - 그래픽 - 여성전용: no; 카스토퍼: yes; 장애인주차 표시: no
Type - 기타 - 카테고리: 주차장; KBIMS-부위코드: E77; 제작정보: bSK-2021_KBIMS2.0-bC; 조달청표준공사코드: CLH2601; 패밀리 이름: SE251-기본주차
Type - 재료 및 마감재 - 보행안전통로 표시선 재료: KBIMS-노면용 페인트_노란색; 여성전용마크 재료: KBIMS-노면용 페인트_분홍색; 장애인마크 재료: KBIMS-노면용 페인트_흰색; 주차표면_일반: KBIMS-에폭시 페인트; 주차표면_장애인용: KBIMS-노면용 페인트_진하늘색
Type - 치수 - 길이: 5200 mm; 마크 두께: 1 mm; 보행안전통로 폭: 1000 mm; 보행안전통로 표시선 두께: 200 mm; 카스토퍼 이격거리(세로): 1100 mm; 폭: 2600 mm
Pset_BuildingElementProxyCommon - Reference: SE251-기본주차 확장형; sets with these values: 2
Pset_ProvisionForVoid - Width: 2600 mm; Height: 5200 mm; Depth: 1.6 mm
공정 - 생성 공정: 새 구성
구속조건 - 가까운 요소로 이동: no; 호스트에서의 간격띄우기: 100 mm
그래픽 - 원점: no
기타 - 패밀리: SE251-기본주차; 유형: SE251-기본주차 확장형; 유형 ID: 3098913; 주차단위구획: 확장형; 주차형식: 직각주차; 패밀리 및 유형: SE251-기본주차: SE251-기본주차 확장형
치수 - 면적: 36.8061 m2; 체적: 0.0654313 m3
Name (SE251-기본주차:SE251-기본주차 확장형:...) | In | 레벨 | 호스트 | Material
3098503 | 125 | 지하2층 | 레벨 : 지하2층
3098504 | 125 | 지하2층 | 레벨 : 지하2층 | KBIMS-고무_검은색, KBIMS-에폭시 페인트
3098506 | 125 | 지하2층 | 레벨 : 지하2층 | KBIMS-고무_검은색, KBIMS-에폭시 페인트
3098507 | 125 | 지하2층 | 레벨 : 지하2층 | KBIMS-고무_검은색, KBIMS-에폭시 페인트
3098508 | 125 | 지하2층 | 레벨 : 지하2층 | KBIMS-고무_검은색, KBIMS-에폭시 페인트
3098509 | 125 | 지하2층 | 레벨 : 지하2층 | KBIMS-고무_검은색, KBIMS-에폭시 페인트
3098510 | 125 | 지하2층 | 레벨 : 지하2층 | KBIMS-고무_검은색, KBIMS-에폭시 페인트
3098511 | 125 | 지하2층 | 레벨 : 지하2층 | KBIMS-고무_검은색, KBIMS-에폭시 페인트
3098512 | 125 | 지하2층 | 레벨 : 지하2층 | KBIMS-고무_검은색, KBIMS-에폭시 페인트
3107492 | 136 | 지하1층 | 레벨 : 지하1층 | KBIMS-고무_검은색, KBIMS-에폭시 페인트
3107493 | 136 | 지하1층 | 레벨 : 지하1층 | KBIMS-고무_검은색, KBIMS-에폭시 페인트

# IfcBuildingElementProxy: VAV Unit_RA:400x250 - 200A - 200A, VAV Unit_RA:400x250 - 200A - 200A:7855257
In: 지상 1층
Type - Material: VAV Unit (4)
Type - ID 데이터 - OmniClass 번호: 23.75.00.00; OmniClass 제목: Climate Control (HVAC); 유형 이름: 400x250 - 200A - 200A
Type - 구속조건 - 기본 높이: 0 mm
Type - 기계 - 분류: 없음
Type - 기타 - 카테고리: 기계 장비; 패밀리 이름: VAV Unit_RA
Pset_BuildingElementProxyCommon - Reference: 400x250 - 200A - 200A; sets with these values: 2
ID 데이터 - 마크: 1
공정 - 생성 공정: 새 구성
구속조건 - 레벨: 지상 1층; 레벨로부터의 높이: 4180 mm; 호스트: 레벨 : 지상 1층; 호스트에서의 간격띄우기: 4180 mm
기계 - 시스템 분류: 순환 공기; 시스템 이름: 기계 Return Air 6,기계 Return Air 7,기계 Return Air 8
기타 - 유형: 400x250 - 200A - 200A; 유형 ID: 7855796; 패밀리: VAV Unit_RA; 패밀리 및 유형: VAV Unit_RA: 400x250 - 200A - 200A
치수 - 면적: 0.656727 m2; 체적: 0.0606413 m3
Group: 모델 그룹:MEP 2:7855242; 기계 Return Air 6; 기계 Return Air 7; 기계 Return Air 8

# IfcBuildingElementProxy: 비상용벨1:비상용벨, 비상용벨1:비상용벨:7705774
In: 188
Type - Material: KBIMS-복합 패널
Type - ID 데이터 - 유형 이름: 비상용벨
Type - 기타 - 카테고리: 일반 모델; 패밀리 이름: 비상용벨1
Pset_BuildingElementProxyCommon - Reference: 비상용벨; sets with these values: 2
Pset_ProvisionForVoid - Width: 204.385 mm; Height: 38.1269 mm; Depth: 79.9536 mm
공정 - 생성 공정: 새 구성
구속조건 - 가까운 요소로 이동: no
기타 - 유형: 비상용벨; 유형 ID: 7705772; 패밀리: 비상용벨1; 패밀리 및 유형: 비상용벨1: 비상용벨
치수 - 면적: 0.00779256 m2; 체적: 0.000623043 m3

# IfcBuildingElementProxy: 비상용벨2:비상용벨, 비상용벨2:비상용벨:7706130
In: 202
Type - Material: KBIMS-복합 패널
Type - ID 데이터 - 유형 이름: 비상용벨
Type - 기타 - 카테고리: 일반 모델; 패밀리 이름: 비상용벨2
Pset_BuildingElementProxyCommon - Reference: 비상용벨; sets with these values: 2
Pset_ProvisionForVoid - Width: 204.385 mm; Height: 38.1269 mm; Depth: 79.9536 mm
공정 - 생성 공정: 새 구성
구속조건 - 가까운 요소로 이동: no
기타 - 유형: 비상용벨; 유형 ID: 7706128; 패밀리: 비상용벨2; 패밀리 및 유형: 비상용벨2: 비상용벨
치수 - 면적: 0.00779256 m2; 체적: 0.000623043 m3

# IfcBuildingElementProxy: 비상용벨3:비상용벨, 비상용벨3:비상용벨:7706187
In: 222
Type - Material: KBIMS-복합 패널
Type - ID 데이터 - 유형 이름: 비상용벨
Type - 기타 - 카테고리: 일반 모델; 패밀리 이름: 비상용벨3
Pset_BuildingElementProxyCommon - Reference: 비상용벨; sets with these values: 2
Pset_ProvisionForVoid - Width: 204.385 mm; Height: 38.1269 mm; Depth: 79.9536 mm
공정 - 생성 공정: 새 구성
구속조건 - 가까운 요소로 이동: no
기타 - 유형: 비상용벨; 유형 ID: 7706185; 패밀리: 비상용벨3; 패밀리 및 유형: 비상용벨3: 비상용벨
치수 - 면적: 0.00779256 m2; 체적: 0.000623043 m3

# IfcBuildingElementProxy: 비상용벨4:비상용벨, 비상용벨4:비상용벨:7706244
In: 225
Type - Material: KBIMS-복합 패널
Type - ID 데이터 - 유형 이름: 비상용벨
Type - 기타 - 카테고리: 일반 모델; 패밀리 이름: 비상용벨4
Pset_BuildingElementProxyCommon - Reference: 비상용벨; sets with these values: 2
Pset_ProvisionForVoid - Width: 204.385 mm; Height: 38.1269 mm; Depth: 79.9536 mm
공정 - 생성 공정: 새 구성
구속조건 - 가까운 요소로 이동: no
기타 - 유형: 비상용벨; 유형 ID: 7706242; 패밀리: 비상용벨4; 패밀리 및 유형: 비상용벨4: 비상용벨
치수 - 면적: 0.00779256 m2; 체적: 0.000623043 m3

# IfcBuildingElementProxy: 비상용벨5:비상용벨, 비상용벨5:비상용벨:7706301
In: 240
Type - Material: KBIMS-복합 패널
Type - ID 데이터 - 유형 이름: 비상용벨
Type - 기타 - 카테고리: 일반 모델; 패밀리 이름: 비상용벨5
Pset_BuildingElementProxyCommon - Reference: 비상용벨; sets with these values: 2
Pset_ProvisionForVoid - Width: 204.385 mm; Height: 38.1269 mm; Depth: 79.9536 mm
공정 - 생성 공정: 새 구성
구속조건 - 가까운 요소로 이동: no
기타 - 유형: 비상용벨; 유형 ID: 7706299; 패밀리: 비상용벨5; 패밀리 및 유형: 비상용벨5: 비상용벨
치수 - 면적: 0.00779256 m2; 체적: 0.000623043 m3

# IfcBuildingElementProxy: 비상용벨6:비상용벨, 비상용벨6:비상용벨:7706358
In: 266
Type - Material: KBIMS-복합 패널
Type - ID 데이터 - 유형 이름: 비상용벨
Type - 기타 - 카테고리: 일반 모델; 패밀리 이름: 비상용벨6
Pset_BuildingElementProxyCommon - Reference: 비상용벨; sets with these values: 2
Pset_ProvisionForVoid - Width: 204.385 mm; Height: 38.1269 mm; Depth: 79.9536 mm
공정 - 생성 공정: 새 구성
구속조건 - 가까운 요소로 이동: no
기타 - 유형: 비상용벨; 유형 ID: 7706356; 패밀리: 비상용벨6; 패밀리 및 유형: 비상용벨6: 비상용벨
치수 - 면적: 0.00779256 m2; 체적: 0.000623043 m3

# IfcBuildingElementProxy: 비상용벨7:비상용벨, 비상용벨7:비상용벨:7706415
In: 278
Type - Material: KBIMS-복합 패널
Type - ID 데이터 - 유형 이름: 비상용벨
Type - 기타 - 카테고리: 일반 모델; 패밀리 이름: 비상용벨7
Pset_BuildingElementProxyCommon - Reference: 비상용벨; sets with these values: 2
Pset_ProvisionForVoid - Width: 204.385 mm; Height: 38.1269 mm; Depth: 79.9536 mm
공정 - 생성 공정: 새 구성
구속조건 - 가까운 요소로 이동: no
기타 - 유형: 비상용벨; 유형 ID: 7706413; 패밀리: 비상용벨7; 패밀리 및 유형: 비상용벨7: 비상용벨
치수 - 면적: 0.00779256 m2; 체적: 0.000623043 m3

# IfcBuildingElementProxy: 비상용벨8:비상용벨, 비상용벨8:비상용벨:7706472
In: 297
Type - Material: KBIMS-복합 패널
Type - ID 데이터 - 유형 이름: 비상용벨
Type - 기타 - 카테고리: 일반 모델; 패밀리 이름: 비상용벨8
Pset_BuildingElementProxyCommon - Reference: 비상용벨; sets with these values: 2
Pset_ProvisionForVoid - Width: 204.385 mm; Height: 38.1269 mm; Depth: 79.9536 mm
공정 - 생성 공정: 새 구성
구속조건 - 가까운 요소로 이동: no
기타 - 유형: 비상용벨; 유형 ID: 7706470; 패밀리: 비상용벨8; 패밀리 및 유형: 비상용벨8: 비상용벨
치수 - 면적: 0.00779256 m2; 체적: 0.000623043 m3

# IfcBuildingElementProxy: 비상용벨9:비상용벨, 비상용벨9:비상용벨:7706529
In: 312
Type - Material: KBIMS-복합 패널
Type - ID 데이터 - 유형 이름: 비상용벨
Type - 기타 - 카테고리: 일반 모델; 패밀리 이름: 비상용벨9
Pset_BuildingElementProxyCommon - Reference: 비상용벨; sets with these values: 2
Pset_ProvisionForVoid - Width: 204.385 mm; Height: 38.1269 mm; Depth: 79.9536 mm
공정 - 생성 공정: 새 구성
구속조건 - 가까운 요소로 이동: no
기타 - 유형: 비상용벨; 유형 ID: 7706527; 패밀리: 비상용벨9; 패밀리 및 유형: 비상용벨9: 비상용벨
치수 - 면적: 0.00779256 m2; 체적: 0.000623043 m3

# IfcBuildingElementProxy: 비상용벨:비상용벨, 비상용벨:비상용벨:7591896
In: 170
Type - Material: KBIMS-복합 패널
Type - ID 데이터 - 유형 이름: 비상용벨
Type - 기타 - 카테고리: 일반 모델; 패밀리 이름: 비상용벨
Pset_BuildingElementProxyCommon - Reference: 비상용벨; sets with these values: 2
Pset_ProvisionForVoid - Width: 204.385 mm; Height: 38.1269 mm; Depth: 81.6174 mm
공정 - 생성 공정: 새 구성
구속조건 - 가까운 요소로 이동: no
기타 - 유형: 비상용벨; 유형 ID: 7591894; 패밀리: 비상용벨; 패밀리 및 유형: 비상용벨: 비상용벨
치수 - 면적: 0.00779256 m2; 체적: 0.000636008 m3

# IfcBuildingElementProxy: 승강기패밀리_리프트카:XX111-승객용 엘리베이터 (13인승) 1600x1350, 승강기패밀리_리프트카:XX111-승객용 엘리베이터 (13인승) 1600x1350:7471662
In: 51
Type - Material: KBIMS-스테인리스(운송) (6)
Type - ID 데이터 - OmniClass 번호: 23.75.00.00; OmniClass 제목: Climate Control (HVAC); 유형 이름: XX111-승객용 엘리베이터 (13인승) 1600x1350
Type - 구속조건 - 기본 높이: 0 mm
Type - 기타 - 카테고리: 일반 모델; KBIMS_보급정보-보급코드: bSK-181231; KBIMS_보급정보-저작자: 빌딩스마트협회; KBIMS_식별-버전: 1.02; 비상용승강기여부: yes; 패밀리 이름: 승강기패밀리_리프트카
Type - 치수 - 가로: 1600 mm; 높이: 2350 mm; 세로: 1350 mm; 와이어 길이: 40850 mm
Pset_BuildingElementProxyCommon - Reference: XX111-승객용 엘리베이터 (13인승) 1600x1350; sets with these values: 2
Pset_ProvisionForVoid - Width: 1600 mm; Height: 1350 mm; Depth: 2350 mm
공정 - 생성 공정: 새 구성
구속조건 - 레벨: 지상 1층; 가까운 요소로 이동: no; 레벨로부터의 높이: 0 mm; 호스트에서의 간격띄우기: 0 mm; 호스트: 레벨 : 지상 1층
기타 - 유형: XX111-승객용 엘리베이터 (13인승) 1600x1350; 유형 ID: 7471454; 패밀리: 승강기패밀리_리프트카; 패밀리 및 유형: 승강기패밀리_리프트카: XX111-승객용 엘리베이터 (13인승) 1600x1350
치수 - 면적: 31.5702 m2; 체적: 5.86201 m3

# IfcBuildingElementProxy: 점형블록1:점형블록, 점형블록1:점형블록:7591625
In: 지상 1층
Type - Material: KBIMS-복합 패널
Type - ID 데이터 - 유형 이름: 점형블록
Type - 기타 - 카테고리: 일반 모델; 패밀리 이름: 점형블록1
Pset_BuildingElementProxyCommon - Reference: 점형블록; sets with these values: 2
Pset_ProvisionForVoid - Width: 400 mm; Height: 400 mm; Depth: 4.39774 mm
공정 - 생성 공정: 새 구성
구속조건 - 가까운 요소로 이동: no
기타 - 유형: 점형블록; 유형 ID: 7591623; 패밀리: 점형블록1; 패밀리 및 유형: 점형블록1: 점형블록
치수 - 면적: 0.16 m2; 체적: 0.000703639 m3

# IfcBuildingElementProxy: 점형블록2:점형블록, 점형블록2:점형블록:7591643
In: 지상 1층
Type - Material: KBIMS-복합 패널
Type - ID 데이터 - 유형 이름: 점형블록
Type - 기타 - 카테고리: 일반 모델; 패밀리 이름: 점형블록2
Pset_BuildingElementProxyCommon - Reference: 점형블록; sets with these values: 2
Pset_ProvisionForVoid - Width: 400 mm; Height: 400 mm; Depth: 4.39774 mm
공정 - 생성 공정: 새 구성
구속조건 - 가까운 요소로 이동: no
기타 - 유형: 점형블록; 유형 ID: 7591641; 패밀리: 점형블록2; 패밀리 및 유형: 점형블록2: 점형블록
치수 - 면적: 0.16 m2; 체적: 0.000703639 m3

# IfcBuildingElementProxy: 점형블록3:점형블록, 점형블록3:점형블록:7591661
In: 지상 1층
Type - Material: KBIMS-복합 패널
Type - ID 데이터 - 유형 이름: 점형블록
Type - 기타 - 카테고리: 일반 모델; 패밀리 이름: 점형블록3
Pset_BuildingElementProxyCommon - Reference: 점형블록; sets with these values: 2
Pset_ProvisionForVoid - Width: 400 mm; Height: 400 mm; Depth: 4.39774 mm
공정 - 생성 공정: 새 구성
구속조건 - 가까운 요소로 이동: no
기타 - 유형: 점형블록; 유형 ID: 7591659; 패밀리: 점형블록3; 패밀리 및 유형: 점형블록3: 점형블록
치수 - 면적: 0.16 m2; 체적: 0.000703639 m3

# IfcBuildingElementProxy: 점형블록4:점형블록, 점형블록4:점형블록:7591683
In: 지상 1층
Type - Material: KBIMS-복합 패널
Type - ID 데이터 - 유형 이름: 점형블록
Type - 기타 - 카테고리: 일반 모델; 패밀리 이름: 점형블록4
Pset_BuildingElementProxyCommon - Reference: 점형블록; sets with these values: 2
Pset_ProvisionForVoid - Width: 400 mm; Height: 400 mm; Depth: 4.39774 mm
공정 - 생성 공정: 새 구성
구속조건 - 가까운 요소로 이동: no
기타 - 유형: 점형블록; 유형 ID: 7591681; 패밀리: 점형블록4; 패밀리 및 유형: 점형블록4: 점형블록
치수 - 면적: 0.16 m2; 체적: 0.000703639 m3

# IfcBuildingElementProxy: 점형블록:점형블록, 점형블록:점형블록:7591314
In: 지상 1층
Type - Material: KBIMS-복합 패널
Type - ID 데이터 - 유형 이름: 점형블록
Type - 기타 - 카테고리: 일반 모델; 패밀리 이름: 점형블록
Pset_BuildingElementProxyCommon - Reference: 점형블록; sets with these values: 2
Pset_ProvisionForVoid - Width: 400 mm; Height: 400 mm; Depth: 4.39774 mm
공정 - 생성 공정: 새 구성
구속조건 - 가까운 요소로 이동: no
기타 - 유형: 점형블록; 유형 ID: 7591312; 패밀리: 점형블록; 패밀리 및 유형: 점형블록: 점형블록
치수 - 면적: 0.16 m2; 체적: 0.000703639 m3

# IfcColumn: CL111-철근콘크리트구조 기둥 (각형)1:CL111-철근콘크리트구조 기둥 (각형)_1020x400_B2-B1C13 (3)
Type - PredefinedType: COLUMN; Material: KBIMS-콘크리트
Type - ID 데이터 - 유형 마크: C13; 유형 이름: CL111-철근콘크리트구조 기둥 (각형)_1020x400_B2-B1C13
Type - 구조 - 단면 모양: 0
Type - 기타 - 내화구조여부: yes; 주요구조부여부: yes; 카테고리: 구조 기둥; KBIMS-부위코드: E22; 제작정보: bSK-2021_KBIMS2.0-bC; 조달청표준공사코드: AD; 패밀리 이름: CL111-철근콘크리트구조 기둥 (각형)1
Type - 재료 및 마감재 - 구조 재료: KBIMS-콘크리트
Type - 치수 - 가로치수: 1020 mm; 세로치수: 400 mm
Type - Pset_ColumnCommon - IsExternal: no; LoadBearing: yes
Pset_ColumnCommon - Reference: CL111-철근콘크리트구조 기둥 (각형)_1020x400_B2-B1C13
Pset_QuantityTakeOff - Reference: CL111-철근콘크리트구조 기둥 (각형)_1020x400_B2-B1C13; sets with these values: 2
ID 데이터 - 연관 있음: no
공정 - 생성 공정: 새 구성
구속조건 - 베이스 간격띄우기: 0 mm; 룸 경계: yes; 상단 간격띄우기: 0 mm; 그리드와 함께 이동: yes; 기둥 스타일: 수직; 기둥 위치 마크: X1(4,510)-Y4
구조 - 보강 철근 피복 - 다른 면: 보강 철근 피복 1 <25 mm>
기타 - 패밀리: CL111-철근콘크리트구조 기둥 (각형)1; 유형: CL111-철근콘크리트구조 기둥 (각형)_1020x400_B2-B1C13; 유형 ID: 7669436; 패밀리 및 유형: CL111-철근콘크리트구조 기둥 (각형)1: CL111-철근콘크리트구조 기둥 (각형)_1020x400_B2-B1C13
치수 - 단면적: 0.408 m2
Name (CL111-철근콘크리트구조 기둥 (각형)1:CL111-철근콘크리트구조 기둥 (각형)_1020x400_B2-B1C13:...) | In | Length (mm) | CrossSectionArea (m2) | OuterSurfaceArea (m2) | GrossVolume (m3) | NetVolume (m3) = 체적 (m3) | 레벨 = 베이스 레벨 | 상단 레벨 | 보강 철근 피복 - 하단 면 | 길이 (mm) | 보강 철근 피복 - 상단 면
7668121 | 지하2층 | 3800 | 0.0963842 | 5.23026 | 0.36626 | 0.36626 | 지하2층 | 지하1층 | 보강 철근 피복 1 <25 mm> | 4000
7668155 | 지하2층 | 1800 | 0.297227 | 5.0029 | 0.535008 | 0.535008 | PIT | 지하2층 | 보강 철근 피복 1 <25 mm> | 1800 | 보강 철근 피복 1 <25 mm>
7668248 | 지하1층 | 5950 | 0.000475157 | 0.72524 | 0.00282718 | 0.939708 | 지하1층 | 지상 1층 |  | 6100 | 보강 철근 피복 1 <25 mm> | Pset_ColumnCommon - Slope: 0 deg

# IfcColumn: CL111-철근콘크리트구조 기둥 (각형)1:CL111-철근콘크리트구조 기둥 (각형)_300x300_RC5 (21)
In: 옥탑층
Type - PredefinedType: COLUMN; Material: KBIMS-콘크리트
Type - ID 데이터 - 유형 마크: C5; 유형 이름: CL111-철근콘크리트구조 기둥 (각형)_300x300_RC5
Type - 구조 - 단면 모양: 0
Type - 기타 - 내화구조여부: yes; 주요구조부여부: yes; 카테고리: 구조 기둥; KBIMS-부위코드: E22; 제작정보: bSK-2021_KBIMS2.0-bC; 조달청표준공사코드: AD; 패밀리 이름: CL111-철근콘크리트구조 기둥 (각형)1
Type - 재료 및 마감재 - 구조 재료: KBIMS-콘크리트
Type - 치수 - 가로치수: 300 mm; 세로치수: 300 mm
Type - Pset_ColumnCommon - IsExternal: no; LoadBearing: yes
BaseQuantities - Length: 740 mm
Pset_ColumnCommon - Reference: CL111-철근콘크리트구조 기둥 (각형)_300x300_RC5
Pset_QuantityTakeOff - Reference: CL111-철근콘크리트구조 기둥 (각형)_300x300_RC5; sets with these values: 2
ID 데이터 - 연관 있음: no
공정 - 생성 공정: 새 구성
구속조건 - 베이스 간격띄우기: 0 mm; 룸 경계: yes; 레벨: 옥탑층; 그리드와 함께 이동: yes; 기둥 스타일: 수직; 베이스 레벨: 옥탑층; 상단 레벨: 지붕층; 상단 간격띄우기: -3260 mm
구조 - 보강 철근 피복 - 다른 면: 보강 철근 피복 1 <25 mm>; 보강 철근 피복 - 상단 면: 보강 철근 피복 1 <25 mm>
기타 - 패밀리: CL111-철근콘크리트구조 기둥 (각형)1; 유형: CL111-철근콘크리트구조 기둥 (각형)_300x300_RC5; 유형 ID: 7669431; 패밀리 및 유형: CL111-철근콘크리트구조 기둥 (각형)1: CL111-철근콘크리트구조 기둥 (각형)_300x300_RC5
치수 - 길이: 740 mm; 단면적: 0.09 m2
Name (CL111-철근콘크리트구조 기둥 (각형)1:CL111-철근콘크리트구조 기둥 (각형)_300x300_RC5:...) | CrossSectionArea (m2) | OuterSurfaceArea (m2) | GrossVolume (m3) = NetVolume (m3) = 체적 (m3) | 기둥 위치 마크
7669116 | 0.09 | 0.888 | 0.0666 | X1(1,000)-Y5(-200)
7669118 | 0.09 | 0.888 | 0.0666 | X1(1,000)-Y4(2,000)
7669120 | 0.09 | 0.888 | 0.0666 | X1(1,000)-Y4(-3,600)
7669122 | 0.09 | 0.888 | 0.0666 | X1(1,000)-Y3(-1,200)
7669124 | 0.09 | 0.888 | 0.0666 | X1(1,000)-Y2
7669126 | 0.09 | 0.888 | 0.0666 | X1(1,000)-Y2(-5,700)
7669128 | 0.09 | 0.888 | 0.0666 | X1(1,000)-Y1(1,000)
7669130 | 0.09 | 0.888 | 0.0666 | X1(6,099)-Y1(1,000)
7669132 | 0.09 | 0.888 | 0.0666 | X2(-2,201)-Y1(1,000)
7669134 | 0.09 | 0.888 | 0.0666 | X3-Y1(1,000)
7669136 | 0.09 | 0.888 | 0.0666 | X3(5,099)-Y1(1,000)
7669138 | 0.09 | 0.888 | 0.0666 | X4(-601)-Y1(1,000)
7669140 | 0.09 | 0.888 | 0.0666 | X4(4,399)-Y1(1,000)
7669142 | 0.09 | 0.888 | 0.0666 | X5(-1,000)-Y1(1,000)
7669144 | 0.09 | 0.888 | 0.0666 | X5(-1,000)-Y2(-5,840)
7669146 | 0.09 | 0.888 | 0.0666 | X5(-1,000)-Y2(-380)
7669148 | 0.09 | 0.888 | 0.0666 | X5(-1,000)-Y3(-1,620)
7669150 | 0.09 | 0.888 | 0.0666 | X5(-1,000)-Y3(3,840)
7669152 | 0.0749182 | 0.813596 | 0.0554394 | X5(-1,000)-Y4(1,300)
7669154 | 0.0749182 | 0.813596 | 0.0554394 | X4(5,250)-Y4(1,300)
7669156 | 0.0749182 | 0.813596 | 0.0554394 | X4(1,000)-Y4(1,300)

# IfcColumn: CL111-철근콘크리트구조 기둥 (각형)1:CL111-철근콘크리트구조 기둥 (각형)_500x500_B2-B1C11 (17)
Type - PredefinedType: COLUMN; Material: KBIMS-콘크리트
Type - ID 데이터 - 유형 마크: C11; 유형 이름: CL111-철근콘크리트구조 기둥 (각형)_500x500_B2-B1C11
Type - 구조 - 단면 모양: 0
Type - 기타 - 내화구조여부: yes; 주요구조부여부: yes; 카테고리: 구조 기둥; KBIMS-부위코드: E22; 제작정보: bSK-2021_KBIMS2.0-bC; 조달청표준공사코드: AD; 패밀리 이름: CL111-철근콘크리트구조 기둥 (각형)1
Type - 재료 및 마감재 - 구조 재료: KBIMS-콘크리트
Type - 치수 - 가로치수: 500 mm; 세로치수: 500 mm
Type - Pset_ColumnCommon - IsExternal: no; LoadBearing: yes
Pset_ColumnCommon - Reference: CL111-철근콘크리트구조 기둥 (각형)_500x500_B2-B1C11
Pset_QuantityTakeOff - Reference: CL111-철근콘크리트구조 기둥 (각형)_500x500_B2-B1C11; sets with these values: 2
ID 데이터 - 연관 있음: no
공정 - 생성 공정: 새 구성
구속조건 - 베이스 간격띄우기: 0 mm; 상단 간격띄우기: 0 mm; 그리드와 함께 이동: yes; 기둥 스타일: 수직
구조 - 보강 철근 피복 - 다른 면: 보강 철근 피복 1 <25 mm>
기타 - 패밀리: CL111-철근콘크리트구조 기둥 (각형)1; 유형: CL111-철근콘크리트구조 기둥 (각형)_500x500_B2-B1C11; 유형 ID: 7669438; 패밀리 및 유형: CL111-철근콘크리트구조 기둥 (각형)1: CL111-철근콘크리트구조 기둥 (각형)_500x500_B2-B1C11
치수 - 단면적: 0.25 m2
Name (CL111-철근콘크리트구조 기둥 (각형)1:CL111-철근콘크리트구조 기둥 (각형)_500x500_B2-B1C11:...) | In | Length (mm) | CrossSectionArea (m2) | OuterSurfaceArea (m2) | GrossVolume (m3) | NetVolume (m3) = 체적 (m3) | 레벨 = 베이스 레벨 | 룸 경계 | 상단 레벨 | 기둥 위치 마크 | 보강 철근 피복 - 상단 면 | 보강 철근 피복 - 하단 면 | 길이 (mm)
7668107 | 지하2층 | 3850 | 0.25 | 7.7 | 0.9625 | 0.9625 | 지하2층 | yes | 지하1층 | X1-Y1(3,500) | 보강 철근 피복 1 <25 mm> | 보강 철근 피복 1 <25 mm> | 4000
7668108 | 지하2층 |  | 4.17864 |  |  | 0.964319 | 지하2층 | yes | 지하1층 | X4-Y1(3,500) | 보강 철근 피복 1 <25 mm> | 보강 철근 피복 1 <25 mm> | 4000
7668109 | 지하2층 |  | 4.14114 |  |  | 0.96341 | 지하2층 | yes | 지하1층 | X5-Y1(3,500) | 보강 철근 피복 1 <25 mm> | 보강 철근 피복 1 <25 mm> | 4000
7668116 | 지하2층 |  | 4.0875 |  |  | 0.956249 | 지하2층 | no | 지하1층 | X1(4,000)-Y3 | 보강 철근 피복 1 <25 mm> | 보강 철근 피복 1 <25 mm> | 4000
7668153 | 지하2층 | 1800 | 0.25 | 3.6 | 0.45 | 0.45 | PIT | yes | 지하2층 | X1(4,000)-Y3 | 보강 철근 피복 1 <25 mm> | 보강 철근 피복 1 <25 mm> | 1800
7668228 | 지하1층 | 5950 | 0.25 | 11.9 | 1.4875 | 1.4875 | 지하1층 | yes | 지상 1층 | X1(2,700)-Y1 |  |  | 6100
7668233 | 지하1층 | 5950 | 0.25 | 11.9 | 1.4875 | 1.4875 | 지하1층 | yes | 지상 1층 | X1-Y1(3,500) | 보강 철근 피복 1 <25 mm> | 보강 철근 피복 1 <25 mm> | 6100
7668234 | 지하1층 | 5950 | 0.25 | 11.9 | 1.4875 | 1.4875 | 지하1층 | yes | 지상 1층 | X1(2,700)-Y1(3,500) | 보강 철근 피복 1 <25 mm> | 보강 철근 피복 1 <25 mm> | 6100
7668235 | 지하1층 | 5950 | 0.25 | 11.9 | 1.4875 | 1.4875 | 지하1층 | yes | 지상 1층 | X3-Y1(3,500) | 보강 철근 피복 1 <25 mm> | 보강 철근 피복 1 <25 mm> | 6100
7668236 | 지하1층 | 5950 | 0.25 | 11.9 | 1.4875 | 1.4875 | 지하1층 | yes | 지상 1층 | X5-Y1(3,500) | 보강 철근 피복 1 <25 mm> | 보강 철근 피복 1 <25 mm> | 6100
7668243 | 지하1층 | 5950 | 0.25 | 11.9 | 1.4875 | 1.4875 | 지하1층 | yes | 지상 1층 | X1(4,000)-Y3 |  | 보강 철근 피복 1 <25 mm> | 6100 | Pset_ColumnCommon - Slope: 0 deg
7669260 | 지하2층 | 3850 | 0.25 | 7.7 | 0.9625 | 0.9625 | 지하2층 | yes | 지하1층 | X1(2,700)-Y1 |  | 보강 철근 피복 1 <25 mm> | 4000
7669261 | 지하2층 | 3850 | 0.25 | 7.7 | 0.9625 | 0.9625 | 지하2층 | yes | 지하1층 | X1(2,700)-Y1(3,500) | 보강 철근 피복 1 <25 mm> | 보강 철근 피복 1 <25 mm> | 4000
7669303 | 지하1층 | 5950 | 0.25 | 11.9 | 1.4875 | 1.4875 | 지하1층 | yes | 지상 1층 | X4-Y1(3,500) | 보강 철근 피복 1 <25 mm> | 보강 철근 피복 1 <25 mm> | 6100
7669307 | 지하2층 |  | 4.18614 |  |  | 0.966194 | 지하2층 | yes | 지하1층 | X3-Y1(3,500) | 보강 철근 피복 1 <25 mm> | 보강 철근 피복 1 <25 mm> | 4000
7669308 | 지하1층 | 5950 | 0.25 | 11.9 | 1.4875 | 1.4875 | 지하1층 | yes | 지상 1층 | X2-Y1(3,500) | 보강 철근 피복 1 <25 mm> | 보강 철근 피복 1 <25 mm> | 6100
7669309 | 지하2층 |  | 4.14113 |  |  | 0.964727 | 지하2층 | yes | 지하1층 | X2-Y1(3,500) | 보강 철근 피복 1 <25 mm> | 보강 철근 피복 1 <25 mm> | 4000

# IfcColumn: CL111-철근콘크리트구조 기둥 (각형)1:CL111-철근콘크리트구조 기둥 (각형)_600x600_B2-10C4 (11)
Type - PredefinedType: COLUMN; Material: KBIMS-콘크리트
Type - ID 데이터 - 유형 마크: C4; 유형 이름: CL111-철근콘크리트구조 기둥 (각형)_600x600_B2-10C4
Type - 구조 - 단면 모양: 0
Type - 기타 - 내화구조여부: yes; 주요구조부여부: yes; 카테고리: 구조 기둥; KBIMS-부위코드: E22; 제작정보: bSK-2021_KBIMS2.0-bC; 조달청표준공사코드: AD; 패밀리 이름: CL111-철근콘크리트구조 기둥 (각형)1
Type - 재료 및 마감재 - 구조 재료: KBIMS-콘크리트
Type - 치수 - 가로치수: 600 mm; 세로치수: 600 mm
Type - Pset_ColumnCommon - IsExternal: no; LoadBearing: yes
Pset_ColumnCommon - Reference: CL111-철근콘크리트구조 기둥 (각형)_600x600_B2-10C4
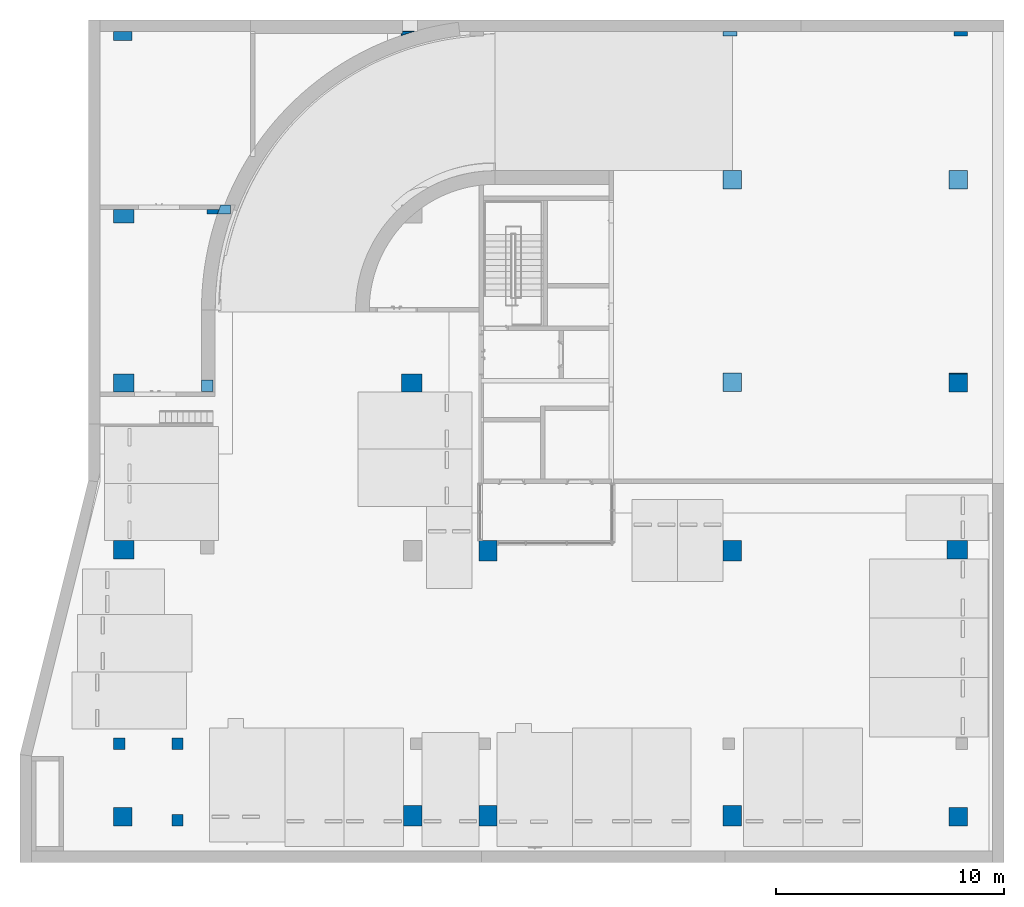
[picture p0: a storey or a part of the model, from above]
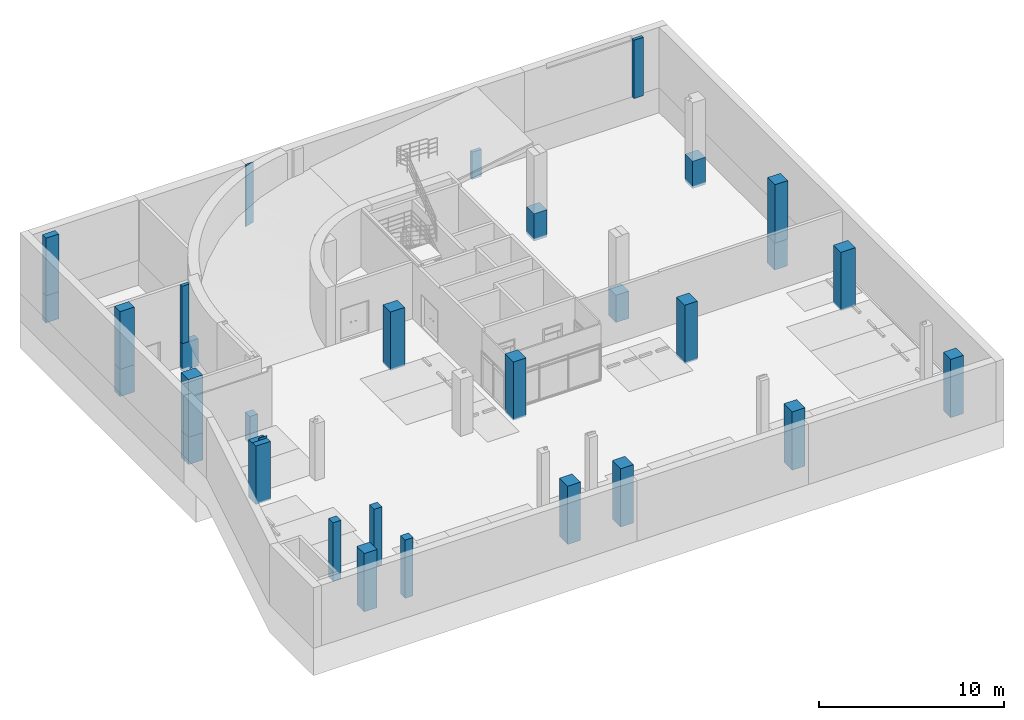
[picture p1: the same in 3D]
Properties of the parts of a building model (IFC2X3), part 10 of 39

# IfcColumn: CL111-철근콘크리트구조 기둥 (각형)1:CL111-철근콘크리트구조 기둥 (각형)_600x600_B2-10C4 (11)
Pset_QuantityTakeOff - Reference: CL111-철근콘크리트구조 기둥 (각형)_600x600_B2-10C4; sets with these values: 2
ID 데이터 - 연관 있음: no
공정 - 생성 공정: 새 구성
구속조건 - 베이스 간격띄우기: 0 mm; 룸 경계: yes; 상단 간격띄우기: 0 mm; 그리드와 함께 이동: yes; 기둥 스타일: 수직; 기둥 위치 마크: X3-Y5
구조 - 보강 철근 피복 - 다른 면: 보강 철근 피복 1 <25 mm>
기타 - 패밀리: CL111-철근콘크리트구조 기둥 (각형)1; 유형: CL111-철근콘크리트구조 기둥 (각형)_600x600_B2-10C4; 유형 ID: 7669437; 패밀리 및 유형: CL111-철근콘크리트구조 기둥 (각형)1: CL111-철근콘크리트구조 기둥 (각형)_600x600_B2-10C4
치수 - 단면적: 0.36 m2
Name (CL111-철근콘크리트구조 기둥 (각형)1:CL111-철근콘크리트구조 기둥 (각형)_600x600_B2-10C4:...) | In | CrossSectionArea (m2) | NetVolume (m3) = 체적 (m3) | 레벨 = 베이스 레벨 | 상단 레벨 | 길이 (mm) | Length (mm) | OuterSurfaceArea (m2) | GrossVolume (m3)
7668127 | 지하2층 | 3.34279 | 0.466907 | 지하2층 | 지하1층 | 4000 | 구조 - 보강 철근 피복 - 상단 면: 보강 철근 피복 1 <25 mm>; 보강 철근 피복 - 하단 면: 보강 철근 피복 1 <25 mm>
7668150 | 지상 1층 | 0.00109236 | 0.745693 | 지상 1층 | 지상 2층 | 4800 | 4650 | 5.59693 | 0.00507947 | 구조 - 보강 철근 피복 - 하단 면: 보강 철근 피복 1 <25 mm>
7668472 | 지상 2층 | 0.160007 | 0.69603 | 지상 2층 | 지상 3층 | 4500 | 4350 | 6.96015 | 0.69603
7668493 | 지상 3층 | 0.160007 | 0.632027 | 지상 3층 | 지상 4층 | 4100 | 3950 | 6.32013 | 0.632027
7668514 | 지상 4층 | 0.160007 | 0.632027 | 지상 4층 | 지상 5층 | 4100 | 3950 | 6.32013 | 0.632027
7668535 | 지상 5층 | 0.160007 | 0.632027 | 지상 5층 | 지상 6층 | 4100 | 3950 | 6.32013 | 0.632027
7668556 | 지상 6층 | 0.160007 | 0.632027 | 지상 6층 | 지상 7층 | 4100 | 3950 | 6.32013 | 0.632027
7668577 | 지상 7층 | 0.160007 | 0.632027 | 지상 7층 | 지상 8층 | 4100 | 3950 | 6.32013 | 0.632027
7668598 | 지상 8층 | 0.160007 | 0.632027 | 지상 8층 | 지상 9층 | 4100 | 3950 | 6.32013 | 0.632027
7668619 | 지상 9층 | 0.160007 | 0.720031 | 지상 9층 | 지상 10층 | 4500 | 4500 | 7.20015 | 0.720031 | 구조 - 보강 철근 피복 - 상단 면: 보강 철근 피복 1 <25 mm>
7668640 | 지상 10층 | 6.36 | 1.77611 | 지상 10층 | 옥탑층 | 5000 | 구조 - 보강 철근 피복 - 상단 면: 보강 철근 피복 1 <25 mm>; 보강 철근 피복 - 하단 면: 보강 철근 피복 1 <25 mm>

# IfcColumn: CL111-철근콘크리트구조 기둥 (각형)1:CL111-철근콘크리트구조 기둥 (각형)_600x600_B2-10C4, CL111-철근콘크리트구조 기둥 (각형)1:CL111-철근콘크리트구조 기둥 (각형)_600x600_B2-10C4:7668254
In: 지하1층
Type - PredefinedType: COLUMN; Material: KBIMS-콘크리트 (2)
Type - ID 데이터 - 유형 마크: C4; 유형 이름: CL111-철근콘크리트구조 기둥 (각형)_600x600_B2-10C4
Type - 구조 - 단면 모양: 0
Type - 기타 - 내화구조여부: yes; 주요구조부여부: yes; 카테고리: 구조 기둥; KBIMS-부위코드: E22; 제작정보: bSK-2021_KBIMS2.0-bC; 조달청표준공사코드: AD; 패밀리 이름: CL111-철근콘크리트구조 기둥 (각형)1
Type - 재료 및 마감재 - 구조 재료: KBIMS-콘크리트
Type - 치수 - 가로치수: 600 mm; 세로치수: 600 mm
Type - Pset_ColumnCommon - IsExternal: no; LoadBearing: yes
BaseQuantities - CrossSectionArea: 4.92041 m2; NetVolume: 0.664182 m3
Pset_ColumnCommon - Reference: CL111-철근콘크리트구조 기둥 (각형)_600x600_B2-10C4
Pset_QuantityTakeOff - Reference: CL111-철근콘크리트구조 기둥 (각형)_600x600_B2-10C4; sets with these values: 2
ID 데이터 - 연관 있음: no
공정 - 생성 공정: 새 구성
구속조건 - 베이스 간격띄우기: 0 mm; 레벨: 지하1층; 룸 경계: yes; 상단 간격띄우기: 0 mm; 그리드와 함께 이동: yes; 기둥 스타일: 수직; 베이스 레벨: 지하1층; 상단 레벨: 지상 1층; 기둥 위치 마크: X3-Y5
구조 - 보강 철근 피복 - 다른 면: 보강 철근 피복 1 <25 mm>; 보강 철근 피복 - 상단 면: 보강 철근 피복 1 <25 mm>; 보강 철근 피복 - 하단 면: 보강 철근 피복 1 <25 mm>
기타 - 패밀리: CL111-철근콘크리트구조 기둥 (각형)1; 유형: CL111-철근콘크리트구조 기둥 (각형)_600x600_B2-10C4; 유형 ID: 7669437; 패밀리 및 유형: CL111-철근콘크리트구조 기둥 (각형)1: CL111-철근콘크리트구조 기둥 (각형)_600x600_B2-10C4
치수 - 길이: 6100 mm; 단면적: 0.36 m2; 체적: 0.664182 m3

# IfcColumn: CL111-철근콘크리트구조 기둥 (각형)1:CL111-철근콘크리트구조 기둥 (각형)_600x600_B2-B2C12 (6)
Type - PredefinedType: COLUMN; Material: KBIMS-콘크리트
Type - ID 데이터 - 유형 마크: C12; 유형 이름: CL111-철근콘크리트구조 기둥 (각형)_600x600_B2-B2C12
Type - 구조 - 단면 모양: 0
Type - 기타 - 내화구조여부: yes; 주요구조부여부: yes; 카테고리: 구조 기둥; KBIMS-부위코드: E22; 제작정보: bSK-2021_KBIMS2.0-bC; 조달청표준공사코드: AD; 패밀리 이름: CL111-철근콘크리트구조 기둥 (각형)1
Type - 재료 및 마감재 - 구조 재료: KBIMS-콘크리트
Type - 치수 - 가로치수: 600 mm; 세로치수: 600 mm
Type - Pset_ColumnCommon - IsExternal: no; LoadBearing: yes
Pset_ColumnCommon - Reference: CL111-철근콘크리트구조 기둥 (각형)_600x600_B2-B2C12
Pset_QuantityTakeOff - Reference: CL111-철근콘크리트구조 기둥 (각형)_600x600_B2-B2C12; sets with these values: 2
ID 데이터 - 연관 있음: no
공정 - 생성 공정: 새 구성
구속조건 - 베이스 간격띄우기: 0 mm; 룸 경계: yes; 그리드와 함께 이동: yes; 기둥 스타일: 수직
구조 - 보강 철근 피복 - 다른 면: 보강 철근 피복 1 <25 mm>; 보강 철근 피복 - 하단 면: 보강 철근 피복 1 <25 mm>
기타 - 패밀리: CL111-철근콘크리트구조 기둥 (각형)1; 유형: CL111-철근콘크리트구조 기둥 (각형)_600x600_B2-B2C12; 유형 ID: 7669432; 패밀리 및 유형: CL111-철근콘크리트구조 기둥 (각형)1: CL111-철근콘크리트구조 기둥 (각형)_600x600_B2-B2C12
치수 - 단면적: 0.36 m2
Name (CL111-철근콘크리트구조 기둥 (각형)1:CL111-철근콘크리트구조 기둥 (각형)_600x600_B2-B2C12:...) | In | Length (mm) | CrossSectionArea (m2) | OuterSurfaceArea (m2) | GrossVolume (m3) | NetVolume (m3) | 레벨 = 베이스 레벨 | 상단 간격띄우기 (mm) | 상단 레벨 | 기둥 위치 마크 | 보강 철근 피복 - 상단 면 | 길이 (mm) | 체적 (m3)
7668129 | 지하2층 | 3850 | 0.119989 | 6.16 | 0.461959 | 0.461944 | 지하2층 | 0 | 지하1층 | X5-Y5 | 보강 철근 피복 1 <25 mm> | 4000 | 0.461944
7668151 | 지하2층 |  | 5.02864 |  |  | 1.38109 | 지하2층 | 0 | 지하1층 | X1(4,000)-Y2 | 보강 철근 피복 1 <25 mm> | 4000 | 1.38109
7668255 | 지상 1층 | 300 | 0.280007 | 0.72 | 0.0840021 | 0.0840021 | 지하1층 | 500 | 지상 1층 | X4-Y5 |  | 6600 | 0.780001
7668256 | 지하1층 | 3800 | 0.12 | 6.08 | 0.455999 | 0.455999 | 지하1층 | -2100 | 지상 1층 | X5-Y5 |  | 4000 | 0.455999
7668257 | 지하1층 | 5950 | 0.36 | 14.28 | 2.142 | 2.142 | 지하1층 | 0 | 지상 1층 | X1(4,000)-Y2 | 보강 철근 피복 1 <25 mm> | 6100 | 2.142
7669266 | 지하2층 | 1800 | 0.12 | 2.88 | 0.216 | 0.216 | PIT | 0 | 지하2층 | X4-Y5 | 보강 철근 피복 1 <25 mm> | 1800 | 0.216

# IfcColumn: CL111-철근콘크리트구조 기둥 (각형)1:CL111-철근콘크리트구조 기둥 (각형)_600x600_B2-B2C12 (2)
Type - PredefinedType: COLUMN; Material: KBIMS-콘크리트 (2)
Type - ID 데이터 - 유형 마크: C12; 유형 이름: CL111-철근콘크리트구조 기둥 (각형)_600x600_B2-B2C12
Type - 구조 - 단면 모양: 0
Type - 기타 - 내화구조여부: yes; 주요구조부여부: yes; 카테고리: 구조 기둥; KBIMS-부위코드: E22; 제작정보: bSK-2021_KBIMS2.0-bC; 조달청표준공사코드: AD; 패밀리 이름: CL111-철근콘크리트구조 기둥 (각형)1
Type - 재료 및 마감재 - 구조 재료: KBIMS-콘크리트
Type - 치수 - 가로치수: 600 mm; 세로치수: 600 mm
Type - Pset_ColumnCommon - IsExternal: no; LoadBearing: yes
Pset_ColumnCommon - Reference: CL111-철근콘크리트구조 기둥 (각형)_600x600_B2-B2C12
Pset_QuantityTakeOff - Reference: CL111-철근콘크리트구조 기둥 (각형)_600x600_B2-B2C12; sets with these values: 2
ID 데이터 - 연관 있음: no
공정 - 생성 공정: 새 구성
구속조건 - 베이스 간격띄우기: 0 mm; 룸 경계: yes; 그리드와 함께 이동: yes; 기둥 스타일: 수직; 기둥 위치 마크: X4-Y5
구조 - 보강 철근 피복 - 다른 면: 보강 철근 피복 1 <25 mm>; 보강 철근 피복 - 하단 면: 보강 철근 피복 1 <25 mm>
기타 - 패밀리: CL111-철근콘크리트구조 기둥 (각형)1; 유형: CL111-철근콘크리트구조 기둥 (각형)_600x600_B2-B2C12; 유형 ID: 7669432; 패밀리 및 유형: CL111-철근콘크리트구조 기둥 (각형)1: CL111-철근콘크리트구조 기둥 (각형)_600x600_B2-B2C12
치수 - 단면적: 0.36 m2
Name (CL111-철근콘크리트구조 기둥 (각형)1:CL111-철근콘크리트구조 기둥 (각형)_600x600_B2-B2C12:...) | In | CrossSectionArea (m2) | NetVolume (m3) | 레벨 = 베이스 레벨 | 상단 간격띄우기 (mm) | 상단 레벨 | 길이 (mm) | 체적 (m3)
7668128 | 지하2층 | 3.2193 | 0.449596 | 지하2층 | 0 | 지하1층 | 4000 | 0.449596 | Pset_ColumnCommon - Slope: 9.36365 deg; 구조 - 보강 철근 피복 - 상단 면: 보강 철근 피복 1 <25 mm>
7668255 | 지하1층 | 5.4016 | 0.695999 | 지하1층 | 500 | 지상 1층 | 6600 | 0.780001

# IfcColumn: CL111-철근콘크리트구조 기둥 (각형)1:CL111-철근콘크리트구조 기둥 (각형)_700x700_5-6C1 (24)
Type - PredefinedType: COLUMN; Material: KBIMS-콘크리트
Type - ID 데이터 - 유형 마크: C1; 유형 이름: CL111-철근콘크리트구조 기둥 (각형)_700x700_5-6C1
Type - 구조 - 단면 모양: 0
Type - 기타 - 내화구조여부: yes; 주요구조부여부: yes; 카테고리: 구조 기둥; KBIMS-부위코드: E22; 제작정보: bSK-2021_KBIMS2.0-bC; 조달청표준공사코드: AD; 패밀리 이름: CL111-철근콘크리트구조 기둥 (각형)1
Type - 재료 및 마감재 - 구조 재료: KBIMS-콘크리트
Type - 치수 - 가로치수: 700 mm; 세로치수: 700 mm
Type - Pset_ColumnCommon - IsExternal: no; LoadBearing: yes
Pset_ColumnCommon - Reference: CL111-철근콘크리트구조 기둥 (각형)_700x700_5-6C1
Pset_QuantityTakeOff - Reference: CL111-철근콘크리트구조 기둥 (각형)_700x700_5-6C1; sets with these values: 2
ID 데이터 - 연관 있음: no
공정 - 생성 공정: 새 구성
구속조건 - 베이스 간격띄우기: 0 mm; 룸 경계: yes; 상단 간격띄우기: 0 mm; 그리드와 함께 이동: yes; 기둥 스타일: 수직
구조 - 보강 철근 피복 - 다른 면: 보강 철근 피복 1 <25 mm>
기타 - 패밀리: CL111-철근콘크리트구조 기둥 (각형)1; 유형: CL111-철근콘크리트구조 기둥 (각형)_700x700_5-6C1; 유형 ID: 7669433; 패밀리 및 유형: CL111-철근콘크리트구조 기둥 (각형)1: CL111-철근콘크리트구조 기둥 (각형)_700x700_5-6C1
치수 - 단면적: 0.49 m2
Name (CL111-철근콘크리트구조 기둥 (각형)1:CL111-철근콘크리트구조 기둥 (각형)_700x700_5-6C1:...) | In | Length (mm) | CrossSectionArea (m2) | OuterSurfaceArea (m2) | GrossVolume (m3) = NetVolume (m3) = 체적 (m3) | 레벨 = 베이스 레벨 | 상단 레벨 | 기둥 위치 마크 | 길이 (mm)
7668527 | 지상 5층 | 3950 | 0.349994 | 9.47993 | 1.38248 | 지상 5층 | 지상 6층 | X4-Y3 | 4100 | 구조 - 보강 철근 피복 - 상단 면: 보강 철근 피복 1 <25 mm>; 보강 철근 피복 - 하단 면: 보강 철근 피복 1 <25 mm>
7668528 | 지상 5층 | 3950 | 0.49 | 11.06 | 1.9355 | 지상 5층 | 지상 6층 | X5-Y3 | 4100 | 구조 - 보강 철근 피복 - 상단 면: 보강 철근 피복 1 <25 mm>; 보강 철근 피복 - 하단 면: 보강 철근 피복 1 <25 mm>
7668531 | 지상 5층 | 3950 | 0.469998 | 11.06 | 1.85649 | 지상 5층 | 지상 6층 | X4-Y4(1,250) | 4100
7668532 | 지상 5층 | 3950 | 0.49 | 11.06 | 1.9355 | 지상 5층 | 지상 6층 | X5-Y4(1,250) | 4100
7668548 | 지상 6층 | 3950 | 0.349994 | 9.47993 | 1.38248 | 지상 6층 | 지상 7층 | X4-Y3 | 4100 | 구조 - 보강 철근 피복 - 상단 면: 보강 철근 피복 1 <25 mm>; 보강 철근 피복 - 하단 면: 보강 철근 피복 1 <25 mm>
7668549 | 지상 6층 | 3950 | 0.49 | 11.06 | 1.9355 | 지상 6층 | 지상 7층 | X5-Y3 | 4100 | 구조 - 보강 철근 피복 - 상단 면: 보강 철근 피복 1 <25 mm>; 보강 철근 피복 - 하단 면: 보강 철근 피복 1 <25 mm>
7668552 | 지상 6층 | 3950 | 0.469998 | 11.06 | 1.85649 | 지상 6층 | 지상 7층 | X4-Y4(1,250) | 4100
7668553 | 지상 6층 | 3950 | 0.49 | 11.06 | 1.9355 | 지상 6층 | 지상 7층 | X5-Y4(1,250) | 4100
7668569 | 지상 7층 | 3950 | 0.349994 | 9.47993 | 1.38248 | 지상 7층 | 지상 8층 | X4-Y3 | 4100 | 구조 - 보강 철근 피복 - 상단 면: 보강 철근 피복 1 <25 mm>; 보강 철근 피복 - 하단 면: 보강 철근 피복 1 <25 mm>
7668570 | 지상 7층 | 3950 | 0.49 | 11.06 | 1.9355 | 지상 7층 | 지상 8층 | X5-Y3 | 4100 | 구조 - 보강 철근 피복 - 상단 면: 보강 철근 피복 1 <25 mm>; 보강 철근 피복 - 하단 면: 보강 철근 피복 1 <25 mm>
7668573 | 지상 7층 | 3950 | 0.469998 | 11.06 | 1.85649 | 지상 7층 | 지상 8층 | X4-Y4(1,250) | 4100
7668574 | 지상 7층 | 3950 | 0.49 | 11.06 | 1.9355 | 지상 7층 | 지상 8층 | X5-Y4(1,250) | 4100
7668590 | 지상 8층 | 3950 | 0.349994 | 9.47993 | 1.38248 | 지상 8층 | 지상 9층 | X4-Y3 | 4100 | 구조 - 보강 철근 피복 - 상단 면: 보강 철근 피복 1 <25 mm>; 보강 철근 피복 - 하단 면: 보강 철근 피복 1 <25 mm>
7668591 | 지상 8층 | 3950 | 0.49 | 11.06 | 1.9355 | 지상 8층 | 지상 9층 | X5-Y3 | 4100 | 구조 - 보강 철근 피복 - 상단 면: 보강 철근 피복 1 <25 mm>; 보강 철근 피복 - 하단 면: 보강 철근 피복 1 <25 mm>
7668594 | 지상 8층 | 3950 | 0.469998 | 11.06 | 1.85649 | 지상 8층 | 지상 9층 | X4-Y4(1,250) | 4100
7668595 | 지상 8층 | 3950 | 0.49 | 11.06 | 1.9355 | 지상 8층 | 지상 9층 | X5-Y4(1,250) | 4100
7668611 | 지상 9층 | 4350 | 0.349994 | 10.4399 | 1.52247 | 지상 9층 | 지상 10층 | X4-Y3 | 4500 | 구조 - 보강 철근 피복 - 상단 면: 보강 철근 피복 1 <25 mm>; 보강 철근 피복 - 하단 면: 보강 철근 피복 1 <25 mm>
7668612 | 지상 9층 | 4350 | 0.49 | 12.18 | 2.1315 | 지상 9층 | 지상 10층 | X5-Y3 | 4500 | 구조 - 보강 철근 피복 - 상단 면: 보강 철근 피복 1 <25 mm>; 보강 철근 피복 - 하단 면: 보강 철근 피복 1 <25 mm>
7668615 | 지상 9층 | 4350 | 0.469998 | 12.18 | 2.04449 | 지상 9층 | 지상 10층 | X4-Y4(1,250) | 4500
7668616 | 지상 9층 | 4350 | 0.49 | 12.18 | 2.1315 | 지상 9층 | 지상 10층 | X5-Y4(1,250) | 4500
7668632 | 지상 10층 | 4770 | 0.3367 | 11.2667 | 1.60606 | 지상 10층 | 옥탑층 | X4-Y3 | 5000 | 구조 - 보강 철근 피복 - 하단 면: 보강 철근 피복 1 <25 mm>
7668633 | 지상 10층 | 4770 | 0.49 | 13.356 | 2.3373 | 지상 10층 | 옥탑층 | X5-Y3 | 5000 | 구조 - 보강 철근 피복 - 하단 면: 보강 철근 피복 1 <25 mm>
7668636 | 지상 10층 | 4770 | 0.49 | 13.356 | 2.3373 | 지상 10층 | 옥탑층 | X4-Y4(1,250) | 5000
7668637 | 지상 10층 | 4770 | 0.49 | 13.356 | 2.3373 | 지상 10층 | 옥탑층 | X5-Y4(1,250) | 5000

# IfcColumn: CL111-철근콘크리트구조 기둥 (각형)1:CL111-철근콘크리트구조 기둥 (각형)_700x700_8-10C2 (39)
Type - PredefinedType: COLUMN; Material: KBIMS-콘크리트
Type - ID 데이터 - 유형 마크: C2; 유형 이름: CL111-철근콘크리트구조 기둥 (각형)_700x700_8-10C2
Type - 구조 - 단면 모양: 0
Type - 기타 - 내화구조여부: yes; 주요구조부여부: yes; 카테고리: 구조 기둥; KBIMS-부위코드: E22; 제작정보: bSK-2021_KBIMS2.0-bC; 조달청표준공사코드: AD; 패밀리 이름: CL111-철근콘크리트구조 기둥 (각형)1
Type - 재료 및 마감재 - 구조 재료: KBIMS-콘크리트
Type - 치수 - 가로치수: 700 mm; 세로치수: 700 mm
Type - Pset_ColumnCommon - IsExternal: no; LoadBearing: yes
Pset_ColumnCommon - Reference: CL111-철근콘크리트구조 기둥 (각형)_700x700_8-10C2
Pset_QuantityTakeOff - Reference: CL111-철근콘크리트구조 기둥 (각형)_700x700_8-10C2; sets with these values: 2
ID 데이터 - 연관 있음: no
공정 - 생성 공정: 새 구성
구속조건 - 베이스 간격띄우기: 0 mm; 룸 경계: yes; 상단 간격띄우기: 0 mm; 그리드와 함께 이동: yes; 기둥 스타일: 수직
구조 - 보강 철근 피복 - 다른 면: 보강 철근 피복 1 <25 mm>
기타 - 패밀리: CL111-철근콘크리트구조 기둥 (각형)1; 유형: CL111-철근콘크리트구조 기둥 (각형)_700x700_8-10C2; 유형 ID: 7669434; 패밀리 및 유형: CL111-철근콘크리트구조 기둥 (각형)1: CL111-철근콘크리트구조 기둥 (각형)_700x700_8-10C2
치수 - 단면적: 0.49 m2
Name (CL111-철근콘크리트구조 기둥 (각형)1:CL111-철근콘크리트구조 기둥 (각형)_700x700_8-10C2:...) | In | Length (mm) | CrossSectionArea (m2) | OuterSurfaceArea (m2) | GrossVolume (m3) | NetVolume (m3) = 체적 (m3) | 레벨 = 베이스 레벨 | 상단 레벨 | 기둥 위치 마크 | 길이 (mm)
7668579 | 지상 8층 | 3950 | 0.49 | 11.06 | 1.9355 | 1.9355 | 지상 8층 | 지상 9층 | X2-Y1 | 4100
7668580 | 지상 8층 | 3950 | 0.49 | 11.06 | 1.9355 | 1.9355 | 지상 8층 | 지상 9층 | X3-Y1 | 4100 | 구조 - 보강 철근 피복 - 상단 면: 보강 철근 피복 1 <25 mm>; 보강 철근 피복 - 하단 면: 보강 철근 피복 1 <25 mm>
7668581 | 지상 8층 | 3950 | 0.49 | 11.06 | 1.9355 | 1.9355 | 지상 8층 | 지상 9층 | X4-Y1 | 4100
7668583 | 지상 8층 | 3950 | 0.49 | 11.06 | 1.9355 | 1.9355 | 지상 8층 | 지상 9층 | X1-Y2 | 4100
7668584 | 지상 8층 | 3950 | 0.49 | 11.06 | 1.9355 | 1.9355 | 지상 8층 | 지상 9층 | X2-Y2 | 4100 | 구조 - 보강 철근 피복 - 상단 면: 보강 철근 피복 1 <25 mm>; 보강 철근 피복 - 하단 면: 보강 철근 피복 1 <25 mm>
7668585 | 지상 8층 | 3950 | 0.49 | 11.06 | 1.9355 | 1.9355 | 지상 8층 | 지상 9층 | X3-Y2 | 4100 | 구조 - 보강 철근 피복 - 상단 면: 보강 철근 피복 1 <25 mm>; 보강 철근 피복 - 하단 면: 보강 철근 피복 1 <25 mm>
7668586 | 지상 8층 | 3950 | 0.49 | 11.06 | 1.9355 | 1.9355 | 지상 8층 | 지상 9층 | X4-Y2 | 4100
7668587 | 지상 8층 | 3950 | 0.49 | 11.06 | 1.9355 | 1.9355 | 지상 8층 | 지상 9층 | X5-Y2 | 4100
7668588 | 지상 8층 | 3950 | 0.49 | 11.06 | 1.9355 | 1.9355 | 지상 8층 | 지상 9층 | X1-Y3 | 4100
7668589 | 지상 8층 | 3950 | 0.49 | 11.06 | 1.9355 | 1.9355 | 지상 8층 | 지상 9층 | X2-Y3 | 4100 | 구조 - 보강 철근 피복 - 상단 면: 보강 철근 피복 1 <25 mm>; 보강 철근 피복 - 하단 면: 보강 철근 피복 1 <25 mm>; Pset_ColumnCommon - Slope: 0 deg
7668592 | 지상 8층 | 3950 | 0.49 | 11.06 | 1.9355 | 1.9355 | 지상 8층 | 지상 9층 | X1-Y4 | 4100
7668593 | 지상 8층 | 3950 | 0.49 | 11.06 | 1.9355 | 1.9355 | 지상 8층 | 지상 9층 | X2-Y4 | 4100 | 구조 - 보강 철근 피복 - 상단 면: 보강 철근 피복 1 <25 mm>; 보강 철근 피복 - 하단 면: 보강 철근 피복 1 <25 mm>
7668597 | 지상 8층 | 3950 | 0.35 | 9.48 | 1.3825 | 1.3825 | 지상 8층 | 지상 9층 | X2-Y5 | 4100 | 구조 - 보강 철근 피복 - 상단 면: 보강 철근 피복 1 <25 mm>; 보강 철근 피복 - 하단 면: 보강 철근 피복 1 <25 mm>
7668600 | 지상 9층 | 4350 | 0.49 | 12.18 | 2.1315 | 2.1315 | 지상 9층 | 지상 10층 | X2-Y1 | 4500
7668601 | 지상 9층 | 4350 | 0.49 | 12.18 | 2.1315 | 2.1315 | 지상 9층 | 지상 10층 | X3-Y1 | 4500 | 구조 - 보강 철근 피복 - 상단 면: 보강 철근 피복 1 <25 mm>; 보강 철근 피복 - 하단 면: 보강 철근 피복 1 <25 mm>
7668602 | 지상 9층 | 4350 | 0.49 | 12.18 | 2.1315 | 2.1315 | 지상 9층 | 지상 10층 | X4-Y1 | 4500
7668604 | 지상 9층 | 4350 | 0.49 | 12.18 | 2.1315 | 2.1315 | 지상 9층 | 지상 10층 | X1-Y2 | 4500
7668605 | 지상 9층 | 4350 | 0.49 | 12.18 | 2.1315 | 2.1315 | 지상 9층 | 지상 10층 | X2-Y2 | 4500 | 구조 - 보강 철근 피복 - 상단 면: 보강 철근 피복 1 <25 mm>; 보강 철근 피복 - 하단 면: 보강 철근 피복 1 <25 mm>
7668606 | 지상 9층 | 4350 | 0.49 | 12.18 | 2.1315 | 2.1315 | 지상 9층 | 지상 10층 | X3-Y2 | 4500 | 구조 - 보강 철근 피복 - 상단 면: 보강 철근 피복 1 <25 mm>; 보강 철근 피복 - 하단 면: 보강 철근 피복 1 <25 mm>
7668607 | 지상 9층 | 4350 | 0.49 | 12.18 | 2.1315 | 2.1315 | 지상 9층 | 지상 10층 | X4-Y2 | 4500 | 구조 - 보강 철근 피복 - 상단 면: 보강 철근 피복 1 <25 mm>
7668608 | 지상 9층 | 4350 | 0.49 | 12.18 | 2.1315 | 2.1315 | 지상 9층 | 지상 10층 | X5-Y2 | 4500
7668609 | 지상 9층 | 4350 | 0.49 | 12.18 | 2.1315 | 2.1315 | 지상 9층 | 지상 10층 | X1-Y3 | 4500
7668610 | 지상 9층 | 4350 | 0.49 | 12.18 | 2.1315 | 2.1315 | 지상 9층 | 지상 10층 | X2-Y3 | 4500 | 구조 - 보강 철근 피복 - 상단 면: 보강 철근 피복 1 <25 mm>; 보강 철근 피복 - 하단 면: 보강 철근 피복 1 <25 mm>
7668613 | 지상 9층 | 4350 | 0.49 | 12.18 | 2.1315 | 2.1315 | 지상 9층 | 지상 10층 | X1-Y4 | 4500
7668614 | 지상 9층 | 4350 | 0.49 | 12.18 | 2.1315 | 2.1315 | 지상 9층 | 지상 10층 | X2-Y4 | 4500 | 구조 - 보강 철근 피복 - 상단 면: 보강 철근 피복 1 <25 mm>; 보강 철근 피복 - 하단 면: 보강 철근 피복 1 <25 mm>
7668618 | 지상 9층 |  | 5.68249 |  |  | 1.54125 | 지상 9층 | 지상 10층 | X2-Y5 | 4500 | 구조 - 보강 철근 피복 - 상단 면: 보강 철근 피복 1 <25 mm>; 보강 철근 피복 - 하단 면: 보강 철근 피복 1 <25 mm>; Pset_ColumnCommon - Slope: 0 deg
7668621 | 지상 10층 | 4770 | 0.49 | 13.356 | 2.3373 | 2.3373 | 지상 10층 | 옥탑층 | X2-Y1 | 5000
7668622 | 지상 10층 | 4770 | 0.49 | 13.356 | 2.3373 | 2.3373 | 지상 10층 | 옥탑층 | X3-Y1 | 5000 | 구조 - 보강 철근 피복 - 하단 면: 보강 철근 피복 1 <25 mm>
7668623 | 지상 10층 | 4770 | 0.49 | 13.356 | 2.3373 | 2.3373 | 지상 10층 | 옥탑층 | X4-Y1 | 5000
7668625 | 지상 10층 | 4770 | 0.49 | 13.356 | 2.3373 | 2.3373 | 지상 10층 | 옥탑층 | X1-Y2 | 5000
7668626 | 지상 10층 | 4770 | 0.49 | 13.356 | 2.3373 | 2.3373 | 지상 10층 | 옥탑층 | X2-Y2 | 5000 | 구조 - 보강 철근 피복 - 하단 면: 보강 철근 피복 1 <25 mm>
7668627 | 지상 10층 | 4770 | 0.49 | 13.356 | 2.3373 | 2.3373 | 지상 10층 | 옥탑층 | X3-Y2 | 5000 | 구조 - 보강 철근 피복 - 하단 면: 보강 철근 피복 1 <25 mm>
7668628 | 지상 10층 | 4770 | 0.49 | 13.356 | 2.3373 | 2.3373 | 지상 10층 | 옥탑층 | X4-Y2 | 5000 | 구조 - 보강 철근 피복 - 하단 면: 보강 철근 피복 1 <25 mm>
7668629 | 지상 10층 | 4770 | 0.49 | 13.356 | 2.3373 | 2.3373 | 지상 10층 | 옥탑층 | X5-Y2 | 5000
7668630 | 지상 10층 | 4770 | 0.49 | 13.356 | 2.3373 | 2.3373 | 지상 10층 | 옥탑층 | X1-Y3 | 5000
7668631 | 지상 10층 | 4770 | 0.49 | 13.356 | 2.3373 | 2.3373 | 지상 10층 | 옥탑층 | X2-Y3 | 5000 | 구조 - 보강 철근 피복 - 하단 면: 보강 철근 피복 1 <25 mm>; Pset_ColumnCommon - Slope: 0 deg
7668634 | 지상 10층 | 4770 | 0.49 | 13.356 | 2.3373 | 2.3373 | 지상 10층 | 옥탑층 | X1-Y4 | 5000
7668635 | 지상 10층 | 4770 | 0.49 | 13.356 | 2.3373 | 2.3373 | 지상 10층 | 옥탑층 | X2-Y4 | 5000 | 구조 - 보강 철근 피복 - 하단 면: 보강 철근 피복 1 <25 mm>
7668639 | 지상 10층 |  | 6.0341 |  |  | 1.61904 | 지상 10층 | 옥탑층 | X2-Y5 | 5000 | 구조 - 보강 철근 피복 - 하단 면: 보강 철근 피복 1 <25 mm>; Pset_ColumnCommon - Slope: 0 deg

# IfcColumn: CL111-철근콘크리트구조 기둥 (각형)1:CL111-철근콘크리트구조 기둥 (각형)_700x700_8-10C3 (9)
Type - PredefinedType: COLUMN; Material: KBIMS-콘크리트
Type - ID 데이터 - 유형 마크: C3; 유형 이름: CL111-철근콘크리트구조 기둥 (각형)_700x700_8-10C3
Type - 구조 - 단면 모양: 0
Type - 기타 - 내화구조여부: yes; 주요구조부여부: yes; 카테고리: 구조 기둥; KBIMS-부위코드: E22; 제작정보: bSK-2021_KBIMS2.0-bC; 조달청표준공사코드: AD; 패밀리 이름: CL111-철근콘크리트구조 기둥 (각형)1
Type - 재료 및 마감재 - 구조 재료: KBIMS-콘크리트
Type - 치수 - 가로치수: 700 mm; 세로치수: 700 mm
Type - Pset_ColumnCommon - IsExternal: no; LoadBearing: yes
BaseQuantities - CrossSectionArea: 0.49 m2
Pset_ColumnCommon - Reference: CL111-철근콘크리트구조 기둥 (각형)_700x700_8-10C3
Pset_QuantityTakeOff - Reference: CL111-철근콘크리트구조 기둥 (각형)_700x700_8-10C3; sets with these values: 2
ID 데이터 - 연관 있음: no
공정 - 생성 공정: 새 구성
구속조건 - 베이스 간격띄우기: 0 mm; 룸 경계: yes; 상단 간격띄우기: 0 mm; 그리드와 함께 이동: yes; 기둥 스타일: 수직
구조 - 보강 철근 피복 - 다른 면: 보강 철근 피복 1 <25 mm>
기타 - 패밀리: CL111-철근콘크리트구조 기둥 (각형)1; 유형: CL111-철근콘크리트구조 기둥 (각형)_700x700_8-10C3; 유형 ID: 7669435; 패밀리 및 유형: CL111-철근콘크리트구조 기둥 (각형)1: CL111-철근콘크리트구조 기둥 (각형)_700x700_8-10C3
치수 - 단면적: 0.49 m2
Name (CL111-철근콘크리트구조 기둥 (각형)1:CL111-철근콘크리트구조 기둥 (각형)_700x700_8-10C3:...) | In | Length (mm) | OuterSurfaceArea (m2) | GrossVolume (m3) = NetVolume (m3) = 체적 (m3) | 레벨 = 베이스 레벨 | 기둥 위치 마크 | 상단 레벨 | 길이 (mm)
7668578 | 지상 8층 | 3950 | 11.06 | 1.9355 | 지상 8층 | X1-Y1 | 지상 9층 | 4100
7668582 | 지상 8층 | 3950 | 11.06 | 1.9355 | 지상 8층 | X5-Y1 | 지상 9층 | 4100
7668596 | 지상 8층 | 3950 | 11.06 | 1.9355 | 지상 8층 | X1-Y5 | 지상 9층 | 4100
7668599 | 지상 9층 | 4350 | 12.18 | 2.1315 | 지상 9층 | X1-Y1 | 지상 10층 | 4500
7668603 | 지상 9층 | 4350 | 12.18 | 2.1315 | 지상 9층 | X5-Y1 | 지상 10층 | 4500
7668617 | 지상 9층 | 4350 | 12.18 | 2.1315 | 지상 9층 | X1-Y5 | 지상 10층 | 4500
7668620 | 지상 10층 | 4770 | 13.356 | 2.3373 | 지상 10층 | X1-Y1 | 옥탑층 | 5000
7668624 | 지상 10층 | 4770 | 13.356 | 2.3373 | 지상 10층 | X5-Y1 | 옥탑층 | 5000
7668638 | 지상 10층 | 4770 | 13.356 | 2.3373 | 지상 10층 | X1-Y5 | 옥탑층 | 5000

# IfcColumn: CL111-철근콘크리트구조 기둥 (각형)1:CL111-철근콘크리트구조 기둥 (각형)_800x800_2-7C2 (78)
Type - PredefinedType: COLUMN; Material: KBIMS-콘크리트
Type - ID 데이터 - 유형 마크: C2; 유형 이름: CL111-철근콘크리트구조 기둥 (각형)_800x800_2-7C2
Type - 구조 - 단면 모양: 0
Type - 기타 - 내화구조여부: yes; 주요구조부여부: yes; 카테고리: 구조 기둥; KBIMS-부위코드: E22; 제작정보: bSK-2021_KBIMS2.0-bC; 조달청표준공사코드: AD; 패밀리 이름: CL111-철근콘크리트구조 기둥 (각형)1
Type - 재료 및 마감재 - 구조 재료: KBIMS-콘크리트
Type - 치수 - 가로치수: 800 mm; 세로치수: 800 mm
Type - Pset_ColumnCommon - IsExternal: no; LoadBearing: yes
Pset_ColumnCommon - Reference: CL111-철근콘크리트구조 기둥 (각형)_800x800_2-7C2
Pset_QuantityTakeOff - Reference: CL111-철근콘크리트구조 기둥 (각형)_800x800_2-7C2; sets with these values: 2
ID 데이터 - 연관 있음: no
공정 - 생성 공정: 새 구성
구속조건 - 베이스 간격띄우기: 0 mm; 룸 경계: yes; 상단 간격띄우기: 0 mm; 그리드와 함께 이동: yes; 기둥 스타일: 수직
구조 - 보강 철근 피복 - 다른 면: 보강 철근 피복 1 <25 mm>
기타 - 패밀리: CL111-철근콘크리트구조 기둥 (각형)1; 유형: CL111-철근콘크리트구조 기둥 (각형)_800x800_2-7C2; 유형 ID: 7669458; 패밀리 및 유형: CL111-철근콘크리트구조 기둥 (각형)1: CL111-철근콘크리트구조 기둥 (각형)_800x800_2-7C2
치수 - 단면적: 0.64 m2
Name (CL111-철근콘크리트구조 기둥 (각형)1:CL111-철근콘크리트구조 기둥 (각형)_800x800_2-7C2:...) | In | Length (mm) | CrossSectionArea (m2) | OuterSurfaceArea (m2) | GrossVolume (m3) = NetVolume (m3) = 체적 (m3) | 레벨 = 베이스 레벨 | 상단 레벨 | 기둥 위치 마크 | 길이 (mm)
7668453 | 지상 2층 | 4350 | 0.64 | 13.92 | 2.784 | 지상 2층 | 지상 3층 | X2-Y1 | 4500
7668454 | 지상 2층 | 4350 | 0.64 | 13.92 | 2.784 | 지상 2층 | 지상 3층 | X3-Y1 | 4500 | 구조 - 보강 철근 피복 - 상단 면: 보강 철근 피복 1 <25 mm>; 보강 철근 피복 - 하단 면: 보강 철근 피복 1 <25 mm>
7668455 | 지상 2층 | 4350 | 0.633748 | 13.92 | 2.7568 | 지상 2층 | 지상 3층 | X4-Y1 | 4500
7668457 | 지상 2층 | 4350 | 0.64 | 13.92 | 2.784 | 지상 2층 | 지상 3층 | X1-Y2 | 4500
7668458 | 지상 2층 | 4350 | 0.64 | 13.92 | 2.784 | 지상 2층 | 지상 3층 | X2-Y2 | 4500 | 구조 - 보강 철근 피복 - 상단 면: 보강 철근 피복 1 <25 mm>; 보강 철근 피복 - 하단 면: 보강 철근 피복 1 <25 mm>
7668459 | 지상 2층 | 4350 | 0.64 | 13.92 | 2.784 | 지상 2층 | 지상 3층 | X3-Y2 | 4500 | 구조 - 보강 철근 피복 - 상단 면: 보강 철근 피복 1 <25 mm>; 보강 철근 피복 - 하단 면: 보강 철근 피복 1 <25 mm>
7668460 | 지상 2층 | 4350 | 0.64 | 13.92 | 2.784 | 지상 2층 | 지상 3층 | X4-Y2 | 4500
7668461 | 지상 2층 | 4350 | 0.64 | 13.92 | 2.784 | 지상 2층 | 지상 3층 | X5-Y2 | 4500
7668462 | 지상 2층 | 4350 | 0.64 | 13.92 | 2.784 | 지상 2층 | 지상 3층 | X1-Y3 | 4500
7668463 | 지상 2층 | 4350 | 0.64 | 13.92 | 2.784 | 지상 2층 | 지상 3층 | X2-Y3 | 4500 | 구조 - 보강 철근 피복 - 상단 면: 보강 철근 피복 1 <25 mm>; 보강 철근 피복 - 하단 면: 보강 철근 피복 1 <25 mm>; Pset_ColumnCommon - Slope: 0 deg
7668466 | 지상 2층 | 4350 | 0.633749 | 13.92 | 2.75681 | 지상 2층 | 지상 3층 | X1-Y4 | 4500
7668467 | 지상 2층 | 4350 | 0.64 | 13.92 | 2.784 | 지상 2층 | 지상 3층 | X2-Y4 | 4500 | 구조 - 보강 철근 피복 - 상단 면: 보강 철근 피복 1 <25 mm>; 보강 철근 피복 - 하단 면: 보강 철근 피복 1 <25 mm>
7668471 | 지상 2층 | 4350 | 0.48 | 12.18 | 2.088 | 지상 2층 | 지상 3층 | X2-Y5 | 4500 | 구조 - 보강 철근 피복 - 상단 면: 보강 철근 피복 1 <25 mm>; 보강 철근 피복 - 하단 면: 보강 철근 피복 1 <25 mm>
7668474 | 지상 3층 | 3950 | 0.64 | 12.64 | 2.528 | 지상 3층 | 지상 4층 | X2-Y1 | 4100
7668475 | 지상 3층 | 3950 | 0.64 | 12.64 | 2.528 | 지상 3층 | 지상 4층 | X3-Y1 | 4100 | 구조 - 보강 철근 피복 - 상단 면: 보강 철근 피복 1 <25 mm>; 보강 철근 피복 - 하단 면: 보강 철근 피복 1 <25 mm>
7668476 | 지상 3층 | 3950 | 0.64 | 12.64 | 2.528 | 지상 3층 | 지상 4층 | X4-Y1 | 4100
7668478 | 지상 3층 | 3950 | 0.64 | 12.64 | 2.528 | 지상 3층 | 지상 4층 | X1-Y2 | 4100
7668479 | 지상 3층 | 3950 | 0.64 | 12.64 | 2.528 | 지상 3층 | 지상 4층 | X2-Y2 | 4100 | 구조 - 보강 철근 피복 - 상단 면: 보강 철근 피복 1 <25 mm>; 보강 철근 피복 - 하단 면: 보강 철근 피복 1 <25 mm>
7668480 | 지상 3층 | 3950 | 0.64 | 12.64 | 2.528 | 지상 3층 | 지상 4층 | X3-Y2 | 4100 | 구조 - 보강 철근 피복 - 상단 면: 보강 철근 피복 1 <25 mm>; 보강 철근 피복 - 하단 면: 보강 철근 피복 1 <25 mm>
7668481 | 지상 3층 | 3950 | 0.64 | 12.64 | 2.528 | 지상 3층 | 지상 4층 | X4-Y2 | 4100
7668482 | 지상 3층 | 3950 | 0.64 | 12.64 | 2.528 | 지상 3층 | 지상 4층 | X5-Y2 | 4100
7668483 | 지상 3층 | 3950 | 0.64 | 12.64 | 2.528 | 지상 3층 | 지상 4층 | X1-Y3 | 4100
7668484 | 지상 3층 | 3950 | 0.64 | 12.64 | 2.528 | 지상 3층 | 지상 4층 | X2-Y3 | 4100 | 구조 - 보강 철근 피복 - 상단 면: 보강 철근 피복 1 <25 mm>; 보강 철근 피복 - 하단 면: 보강 철근 피복 1 <25 mm>; Pset_ColumnCommon - Slope: 0 deg
7668487 | 지상 3층 | 3950 | 0.64 | 12.64 | 2.528 | 지상 3층 | 지상 4층 | X1-Y4 | 4100
7668488 | 지상 3층 | 3950 | 0.64 | 12.64 | 2.528 | 지상 3층 | 지상 4층 | X2-Y4 | 4100 | 구조 - 보강 철근 피복 - 상단 면: 보강 철근 피복 1 <25 mm>; 보강 철근 피복 - 하단 면: 보강 철근 피복 1 <25 mm>
7668492 | 지상 3층 | 3950 | 0.48 | 11.06 | 1.896 | 지상 3층 | 지상 4층 | X2-Y5 | 4100 | 구조 - 보강 철근 피복 - 상단 면: 보강 철근 피복 1 <25 mm>; 보강 철근 피복 - 하단 면: 보강 철근 피복 1 <25 mm>
7668495 | 지상 4층 | 3950 | 0.64 | 12.64 | 2.528 | 지상 4층 | 지상 5층 | X2-Y1 | 4100
7668496 | 지상 4층 | 3950 | 0.64 | 12.64 | 2.528 | 지상 4층 | 지상 5층 | X3-Y1 | 4100 | 구조 - 보강 철근 피복 - 상단 면: 보강 철근 피복 1 <25 mm>; 보강 철근 피복 - 하단 면: 보강 철근 피복 1 <25 mm>
7668497 | 지상 4층 | 3950 | 0.64 | 12.64 | 2.528 | 지상 4층 | 지상 5층 | X4-Y1 | 4100
7668499 | 지상 4층 | 3950 | 0.64 | 12.64 | 2.528 | 지상 4층 | 지상 5층 | X1-Y2 | 4100
7668500 | 지상 4층 | 3950 | 0.64 | 12.64 | 2.528 | 지상 4층 | 지상 5층 | X2-Y2 | 4100 | 구조 - 보강 철근 피복 - 상단 면: 보강 철근 피복 1 <25 mm>; 보강 철근 피복 - 하단 면: 보강 철근 피복 1 <25 mm>
7668501 | 지상 4층 | 3950 | 0.64 | 12.64 | 2.528 | 지상 4층 | 지상 5층 | X3-Y2 | 4100 | 구조 - 보강 철근 피복 - 상단 면: 보강 철근 피복 1 <25 mm>; 보강 철근 피복 - 하단 면: 보강 철근 피복 1 <25 mm>
7668502 | 지상 4층 | 3950 | 0.64 | 12.64 | 2.528 | 지상 4층 | 지상 5층 | X4-Y2 | 4100
7668503 | 지상 4층 | 3950 | 0.64 | 12.64 | 2.528 | 지상 4층 | 지상 5층 | X5-Y2 | 4100
7668504 | 지상 4층 | 3950 | 0.64 | 12.64 | 2.528 | 지상 4층 | 지상 5층 | X1-Y3 | 4100
7668505 | 지상 4층 | 3950 | 0.64 | 12.64 | 2.528 | 지상 4층 | 지상 5층 | X2-Y3 | 4100 | 구조 - 보강 철근 피복 - 상단 면: 보강 철근 피복 1 <25 mm>; 보강 철근 피복 - 하단 면: 보강 철근 피복 1 <25 mm>; Pset_ColumnCommon - Slope: 0 deg
7668508 | 지상 4층 | 3950 | 0.64 | 12.64 | 2.528 | 지상 4층 | 지상 5층 | X1-Y4 | 4100
7668509 | 지상 4층 | 3950 | 0.64 | 12.64 | 2.528 | 지상 4층 | 지상 5층 | X2-Y4 | 4100 | 구조 - 보강 철근 피복 - 상단 면: 보강 철근 피복 1 <25 mm>; 보강 철근 피복 - 하단 면: 보강 철근 피복 1 <25 mm>
7668513 | 지상 4층 | 3950 | 0.48 | 11.06 | 1.896 | 지상 4층 | 지상 5층 | X2-Y5 | 4100 | 구조 - 보강 철근 피복 - 상단 면: 보강 철근 피복 1 <25 mm>; 보강 철근 피복 - 하단 면: 보강 철근 피복 1 <25 mm>
7668516 | 지상 5층 | 3950 | 0.64 | 12.64 | 2.528 | 지상 5층 | 지상 6층 | X2-Y1 | 4100
7668517 | 지상 5층 | 3950 | 0.64 | 12.64 | 2.528 | 지상 5층 | 지상 6층 | X3-Y1 | 4100 | 구조 - 보강 철근 피복 - 상단 면: 보강 철근 피복 1 <25 mm>; 보강 철근 피복 - 하단 면: 보강 철근 피복 1 <25 mm>
7668518 | 지상 5층 | 3950 | 0.64 | 12.64 | 2.528 | 지상 5층 | 지상 6층 | X4-Y1 | 4100
7668520 | 지상 5층 | 3950 | 0.64 | 12.64 | 2.528 | 지상 5층 | 지상 6층 | X1-Y2 | 4100
7668521 | 지상 5층 | 3950 | 0.64 | 12.64 | 2.528 | 지상 5층 | 지상 6층 | X2-Y2 | 4100 | 구조 - 보강 철근 피복 - 상단 면: 보강 철근 피복 1 <25 mm>; 보강 철근 피복 - 하단 면: 보강 철근 피복 1 <25 mm>
7668522 | 지상 5층 | 3950 | 0.64 | 12.64 | 2.528 | 지상 5층 | 지상 6층 | X3-Y2 | 4100 | 구조 - 보강 철근 피복 - 상단 면: 보강 철근 피복 1 <25 mm>; 보강 철근 피복 - 하단 면: 보강 철근 피복 1 <25 mm>
7668523 | 지상 5층 | 3950 | 0.64 | 12.64 | 2.528 | 지상 5층 | 지상 6층 | X4-Y2 | 4100
7668524 | 지상 5층 | 3950 | 0.64 | 12.64 | 2.528 | 지상 5층 | 지상 6층 | X5-Y2 | 4100
7668525 | 지상 5층 | 3950 | 0.64 | 12.64 | 2.528 | 지상 5층 | 지상 6층 | X1-Y3 | 4100
7668526 | 지상 5층 | 3950 | 0.64 | 12.64 | 2.528 | 지상 5층 | 지상 6층 | X2-Y3 | 4100 | 구조 - 보강 철근 피복 - 상단 면: 보강 철근 피복 1 <25 mm>; 보강 철근 피복 - 하단 면: 보강 철근 피복 1 <25 mm>; Pset_ColumnCommon - Slope: 0 deg
7668529 | 지상 5층 | 3950 | 0.64 | 12.64 | 2.528 | 지상 5층 | 지상 6층 | X1-Y4 | 4100
7668530 | 지상 5층 | 3950 | 0.64 | 12.64 | 2.528 | 지상 5층 | 지상 6층 | X2-Y4 | 4100 | 구조 - 보강 철근 피복 - 상단 면: 보강 철근 피복 1 <25 mm>; 보강 철근 피복 - 하단 면: 보강 철근 피복 1 <25 mm>
7668534 | 지상 5층 | 3950 | 0.48 | 11.06 | 1.896 | 지상 5층 | 지상 6층 | X2-Y5 | 4100 | 구조 - 보강 철근 피복 - 상단 면: 보강 철근 피복 1 <25 mm>; 보강 철근 피복 - 하단 면: 보강 철근 피복 1 <25 mm>
7668537 | 지상 6층 | 3950 | 0.64 | 12.64 | 2.528 | 지상 6층 | 지상 7층 | X2-Y1 | 4100
7668538 | 지상 6층 | 3950 | 0.64 | 12.64 | 2.528 | 지상 6층 | 지상 7층 | X3-Y1 | 4100 | 구조 - 보강 철근 피복 - 상단 면: 보강 철근 피복 1 <25 mm>; 보강 철근 피복 - 하단 면: 보강 철근 피복 1 <25 mm>
7668539 | 지상 6층 | 3950 | 0.64 | 12.64 | 2.528 | 지상 6층 | 지상 7층 | X4-Y1 | 4100
7668541 | 지상 6층 | 3950 | 0.64 | 12.64 | 2.528 | 지상 6층 | 지상 7층 | X1-Y2 | 4100
7668542 | 지상 6층 | 3950 | 0.64 | 12.64 | 2.528 | 지상 6층 | 지상 7층 | X2-Y2 | 4100 | 구조 - 보강 철근 피복 - 상단 면: 보강 철근 피복 1 <25 mm>; 보강 철근 피복 - 하단 면: 보강 철근 피복 1 <25 mm>
7668543 | 지상 6층 | 3950 | 0.64 | 12.64 | 2.528 | 지상 6층 | 지상 7층 | X3-Y2 | 4100 | 구조 - 보강 철근 피복 - 상단 면: 보강 철근 피복 1 <25 mm>; 보강 철근 피복 - 하단 면: 보강 철근 피복 1 <25 mm>
7668544 | 지상 6층 | 3950 | 0.64 | 12.64 | 2.528 | 지상 6층 | 지상 7층 | X4-Y2 | 4100
7668545 | 지상 6층 | 3950 | 0.64 | 12.64 | 2.528 | 지상 6층 | 지상 7층 | X5-Y2 | 4100
7668546 | 지상 6층 | 3950 | 0.64 | 12.64 | 2.528 | 지상 6층 | 지상 7층 | X1-Y3 | 4100
7668547 | 지상 6층 | 3950 | 0.64 | 12.64 | 2.528 | 지상 6층 | 지상 7층 | X2-Y3 | 4100 | 구조 - 보강 철근 피복 - 상단 면: 보강 철근 피복 1 <25 mm>; 보강 철근 피복 - 하단 면: 보강 철근 피복 1 <25 mm>; Pset_ColumnCommon - Slope: 0 deg
7668550 | 지상 6층 | 3950 | 0.64 | 12.64 | 2.528 | 지상 6층 | 지상 7층 | X1-Y4 | 4100
7668551 | 지상 6층 | 3950 | 0.64 | 12.64 | 2.528 | 지상 6층 | 지상 7층 | X2-Y4 | 4100 | 구조 - 보강 철근 피복 - 상단 면: 보강 철근 피복 1 <25 mm>; 보강 철근 피복 - 하단 면: 보강 철근 피복 1 <25 mm>
7668555 | 지상 6층 | 3950 | 0.48 | 11.06 | 1.896 | 지상 6층 | 지상 7층 | X2-Y5 | 4100 | 구조 - 보강 철근 피복 - 상단 면: 보강 철근 피복 1 <25 mm>; 보강 철근 피복 - 하단 면: 보강 철근 피복 1 <25 mm>
7668558 | 지상 7층 | 3950 | 0.64 | 12.64 | 2.528 | 지상 7층 | 지상 8층 | X2-Y1 | 4100
7668559 | 지상 7층 | 3950 | 0.64 | 12.64 | 2.528 | 지상 7층 | 지상 8층 | X3-Y1 | 4100 | 구조 - 보강 철근 피복 - 상단 면: 보강 철근 피복 1 <25 mm>; 보강 철근 피복 - 하단 면: 보강 철근 피복 1 <25 mm>
7668560 | 지상 7층 | 3950 | 0.64 | 12.64 | 2.528 | 지상 7층 | 지상 8층 | X4-Y1 | 4100
7668562 | 지상 7층 | 3950 | 0.64 | 12.64 | 2.528 | 지상 7층 | 지상 8층 | X1-Y2 | 4100
7668563 | 지상 7층 | 3950 | 0.64 | 12.64 | 2.528 | 지상 7층 | 지상 8층 | X2-Y2 | 4100 | 구조 - 보강 철근 피복 - 상단 면: 보강 철근 피복 1 <25 mm>; 보강 철근 피복 - 하단 면: 보강 철근 피복 1 <25 mm>
7668564 | 지상 7층 | 3950 | 0.64 | 12.64 | 2.528 | 지상 7층 | 지상 8층 | X3-Y2 | 4100 | 구조 - 보강 철근 피복 - 상단 면: 보강 철근 피복 1 <25 mm>; 보강 철근 피복 - 하단 면: 보강 철근 피복 1 <25 mm>
7668565 | 지상 7층 | 3950 | 0.64 | 12.64 | 2.528 | 지상 7층 | 지상 8층 | X4-Y2 | 4100
7668566 | 지상 7층 | 3950 | 0.64 | 12.64 | 2.528 | 지상 7층 | 지상 8층 | X5-Y2 | 4100
7668567 | 지상 7층 | 3950 | 0.64 | 12.64 | 2.528 | 지상 7층 | 지상 8층 | X1-Y3 | 4100
7668568 | 지상 7층 | 3950 | 0.64 | 12.64 | 2.528 | 지상 7층 | 지상 8층 | X2-Y3 | 4100 | 구조 - 보강 철근 피복 - 상단 면: 보강 철근 피복 1 <25 mm>; 보강 철근 피복 - 하단 면: 보강 철근 피복 1 <25 mm>; Pset_ColumnCommon - Slope: 0 deg
7668571 | 지상 7층 | 3950 | 0.64 | 12.64 | 2.528 | 지상 7층 | 지상 8층 | X1-Y4 | 4100
7668572 | 지상 7층 | 3950 | 0.64 | 12.64 | 2.528 | 지상 7층 | 지상 8층 | X2-Y4 | 4100 | 구조 - 보강 철근 피복 - 상단 면: 보강 철근 피복 1 <25 mm>; 보강 철근 피복 - 하단 면: 보강 철근 피복 1 <25 mm>
7668576 | 지상 7층 | 3950 | 0.48 | 11.06 | 1.896 | 지상 7층 | 지상 8층 | X2-Y5 | 4100 | 구조 - 보강 철근 피복 - 상단 면: 보강 철근 피복 1 <25 mm>; 보강 철근 피복 - 하단 면: 보강 철근 피복 1 <25 mm>

# IfcColumn: CL111-철근콘크리트구조 기둥 (각형)1:CL111-철근콘크리트구조 기둥 (각형)_800x800_B2-4C1 (27)
Type - PredefinedType: COLUMN; Material: KBIMS-콘크리트
Type - ID 데이터 - 유형 마크: C1; 유형 이름: CL111-철근콘크리트구조 기둥 (각형)_800x800_B2-4C1
Type - 구조 - 단면 모양: 0
Type - 기타 - 내화구조여부: yes; 주요구조부여부: yes; 카테고리: 구조 기둥; KBIMS-부위코드: E22; 제작정보: bSK-2021_KBIMS2.0-bC; 조달청표준공사코드: AD; 패밀리 이름: CL111-철근콘크리트구조 기둥 (각형)1
Type - 재료 및 마감재 - 구조 재료: KBIMS-콘크리트
Type - 치수 - 가로치수: 800 mm; 세로치수: 800 mm
Type - Pset_ColumnCommon - IsExternal: no; LoadBearing: yes
Pset_ColumnCommon - Reference: CL111-철근콘크리트구조 기둥 (각형)_800x800_B2-4C1
Pset_QuantityTakeOff - Reference: CL111-철근콘크리트구조 기둥 (각형)_800x800_B2-4C1; sets with these values: 2
ID 데이터 - 연관 있음: no
공정 - 생성 공정: 새 구성
구속조건 - 베이스 간격띄우기: 0 mm; 룸 경계: yes; 상단 간격띄우기: 0 mm; 그리드와 함께 이동: yes; 기둥 스타일: 수직
구조 - 보강 철근 피복 - 다른 면: 보강 철근 피복 1 <25 mm>
기타 - 패밀리: CL111-철근콘크리트구조 기둥 (각형)1; 유형: CL111-철근콘크리트구조 기둥 (각형)_800x800_B2-4C1; 유형 ID: 7669456; 패밀리 및 유형: CL111-철근콘크리트구조 기둥 (각형)1: CL111-철근콘크리트구조 기둥 (각형)_800x800_B2-4C1
치수 - 단면적: 0.64 m2
Name (CL111-철근콘크리트구조 기둥 (각형)1:CL111-철근콘크리트구조 기둥 (각형)_800x800_B2-4C1:...) | In | CrossSectionArea (m2) | NetVolume (m3) = 체적 (m3) | 레벨 = 베이스 레벨 | 상단 레벨 | 기둥 위치 마크 | 보강 철근 피복 - 상단 면 | 보강 철근 피복 - 하단 면 | 길이 (mm) | Length (mm) | OuterSurfaceArea (m2) | GrossVolume (m3)
7668118 | 지하2층 | 6.78 | 2.448 | 지하2층 | 지하1층 | X4-Y3 | 보강 철근 피복 1 <25 mm> | 보강 철근 피복 1 <25 mm> | 4000
7668119 | 지하2층 | 0.64 | 2.464 | 지하2층 | 지하1층 | X5-Y3 | 보강 철근 피복 1 <25 mm> | 보강 철근 피복 1 <25 mm> | 4000 | 3850 | 12.32 | 2.464
7668123 | 지하2층 | 6.78 | 2.448 | 지하2층 | 지하1층 | X4-Y4(1,200) | 보강 철근 피복 1 <25 mm> | 보강 철근 피복 1 <25 mm> | 4000
7668124 | 지하2층 | 6.8 | 2.452 | 지하2층 | 지하1층 | X5-Y4(1,200) | 보강 철근 피복 1 <25 mm> | 보강 철근 피복 1 <25 mm> | 4000
7668142 | 지상 1층 | 0.480007 | 2.23203 | 지상 1층 | 지상 2층 | X4-Y3 | 보강 철근 피복 1 <25 mm> | 보강 철근 피복 1 <25 mm> | 4800 | 4650 | 13.0201 | 2.23203
7668143 | 지상 1층 | 0.64 | 2.976 | 지상 1층 | 지상 2층 | X5-Y3 | 보강 철근 피복 1 <25 mm> | 보강 철근 피복 1 <25 mm> | 4800 | 4650 | 14.88 | 2.976
7668146 | 지상 1층 | 0.5598 | 2.60307 | 지상 1층 | 지상 2층 | X4-Y4(1,200) |  | 보강 철근 피복 1 <25 mm> | 4800 | 4650 | 14.88 | 2.60307
7668147 | 지상 1층 | 0.64 | 2.976 | 지상 1층 | 지상 2층 | X5-Y4(1,200) |  | 보강 철근 피복 1 <25 mm> | 4800 | 4650 | 14.88 | 2.976
7668245 | 지하1층 | 10.9275 | 3.68 | 지하1층 | 지상 1층 | X4-Y3 | 보강 철근 피복 1 <25 mm> | 보강 철근 피복 1 <25 mm> | 6100
7668246 | 지하1층 | 11.18 | 3.76 | 지하1층 | 지상 1층 | X5-Y3 | 보강 철근 피복 1 <25 mm> | 보강 철근 피복 1 <25 mm> | 6100
7668251 | 지하1층 | 0.64 | 3.808 | 지하1층 | 지상 1층 | X5-Y4(1,200) | 보강 철근 피복 1 <25 mm> | 보강 철근 피복 1 <25 mm> | 6100 | 1500 | 4.8 | 0.96
7668464 | 지상 2층 | 0.479993 | 2.08797 | 지상 2층 | 지상 3층 | X4-Y3 | 보강 철근 피복 1 <25 mm> | 보강 철근 피복 1 <25 mm> | 4500 | 4350 | 12.1799 | 2.08797
7668465 | 지상 2층 | 0.64 | 2.784 | 지상 2층 | 지상 3층 | X5-Y3 | 보강 철근 피복 1 <25 mm> | 보강 철근 피복 1 <25 mm> | 4500 | 4350 | 13.92 | 2.784
7668468 | 지상 2층 | 0.619998 | 2.69699 | 지상 2층 | 지상 3층 | X4-Y4(1,200) |  |  | 4500 | 4350 | 13.92 | 2.69699
7668469 | 지상 2층 | 0.639875 | 2.78346 | 지상 2층 | 지상 3층 | X5-Y4(1,200) |  |  | 4500 | 4350 | 13.92 | 2.78346
7668485 | 지상 3층 | 0.479993 | 1.89597 | 지상 3층 | 지상 4층 | X4-Y3 | 보강 철근 피복 1 <25 mm> | 보강 철근 피복 1 <25 mm> | 4100 | 3950 | 11.0599 | 1.89597
7668486 | 지상 3층 | 0.64 | 2.528 | 지상 3층 | 지상 4층 | X5-Y3 | 보강 철근 피복 1 <25 mm> | 보강 철근 피복 1 <25 mm> | 4100 | 3950 | 12.64 | 2.528
7668489 | 지상 3층 | 0.619998 | 2.44899 | 지상 3층 | 지상 4층 | X4-Y4(1,200) |  |  | 4100 | 3950 | 12.64 | 2.44899
7668490 | 지상 3층 | 0.64 | 2.528 | 지상 3층 | 지상 4층 | X5-Y4(1,200) |  |  | 4100 | 3950 | 12.64 | 2.528
7668506 | 지상 4층 | 0.479993 | 1.89597 | 지상 4층 | 지상 5층 | X4-Y3 | 보강 철근 피복 1 <25 mm> | 보강 철근 피복 1 <25 mm> | 4100 | 3950 | 11.0599 | 1.89597
7668507 | 지상 4층 | 0.64 | 2.528 | 지상 4층 | 지상 5층 | X5-Y3 | 보강 철근 피복 1 <25 mm> | 보강 철근 피복 1 <25 mm> | 4100 | 3950 | 12.64 | 2.528
7668510 | 지상 4층 | 0.619802 | 2.44822 | 지상 4층 | 지상 5층 | X4-Y4(1,200) |  |  | 4100 | 3950 | 12.64 | 2.44822
7668511 | 지상 4층 | 0.64 | 2.528 | 지상 4층 | 지상 5층 | X5-Y4(1,200) |  |  | 4100 | 3950 | 12.64 | 2.528
7669262 | 지하2층 | 0.64 | 1.152 | PIT | 지하2층 | X4-Y3 | 보강 철근 피복 1 <25 mm> | 보강 철근 피복 1 <25 mm> | 1800 | 1800 | 5.76 | 1.152
7669263 | 지하2층 | 0.64 | 1.152 | PIT | 지하2층 | X5-Y3 | 보강 철근 피복 1 <25 mm> | 보강 철근 피복 1 <25 mm> | 1800 | 1800 | 5.76 | 1.152
7669264 | 지하2층 | 0.64 | 1.152 | PIT | 지하2층 | X4-Y4(1,200) | 보강 철근 피복 1 <25 mm> | 보강 철근 피복 1 <25 mm> | 1800 | 1800 | 5.76 | 1.152
7669265 | 지하2층 | 0.64 | 1.152 | PIT | 지하2층 | X5-Y4(1,200) | 보강 철근 피복 1 <25 mm> | 보강 철근 피복 1 <25 mm> | 1800 | 1800 | 5.76 | 1.152

# IfcColumn: CL111-철근콘크리트구조 기둥 (각형)1:CL111-철근콘크리트구조 기둥 (각형)_800x800_B2-4C1, CL111-철근콘크리트구조 기둥 (각형)1:CL111-철근콘크리트구조 기둥 (각형)_800x800_B2-4C1:7668250
In: 지하1층
Type - PredefinedType: COLUMN; Material: KBIMS-콘크리트 (2)
Type - ID 데이터 - 유형 마크: C1; 유형 이름: CL111-철근콘크리트구조 기둥 (각형)_800x800_B2-4C1
Type - 구조 - 단면 모양: 0
Type - 기타 - 내화구조여부: yes; 주요구조부여부: yes; 카테고리: 구조 기둥; KBIMS-부위코드: E22; 제작정보: bSK-2021_KBIMS2.0-bC; 조달청표준공사코드: AD; 패밀리 이름: CL111-철근콘크리트구조 기둥 (각형)1
Type - 재료 및 마감재 - 구조 재료: KBIMS-콘크리트
Type - 치수 - 가로치수: 800 mm; 세로치수: 800 mm
Type - Pset_ColumnCommon - IsExternal: no; LoadBearing: yes
BaseQuantities - Length: 4450 mm; CrossSectionArea: 0.519995 m2; OuterSurfaceArea: 14.24 m2; GrossVolume: 2.31398 m3; NetVolume: 3.07767 m3
Pset_ColumnCommon - Reference: CL111-철근콘크리트구조 기둥 (각형)_800x800_B2-4C1
Pset_QuantityTakeOff - Reference: CL111-철근콘크리트구조 기둥 (각형)_800x800_B2-4C1; sets with these values: 2
ID 데이터 - 연관 있음: no
공정 - 생성 공정: 새 구성
구속조건 - 베이스 간격띄우기: 0 mm; 레벨: 지하1층; 룸 경계: yes; 상단 간격띄우기: 0 mm; 그리드와 함께 이동: yes; 기둥 스타일: 수직; 베이스 레벨: 지하1층; 상단 레벨: 지상 1층; 기둥 위치 마크: X4-Y4(1,200)
구조 - 보강 철근 피복 - 다른 면: 보강 철근 피복 1 <25 mm>; 보강 철근 피복 - 상단 면: 보강 철근 피복 1 <25 mm>; 보강 철근 피복 - 하단 면: 보강 철근 피복 1 <25 mm>
기타 - 패밀리: CL111-철근콘크리트구조 기둥 (각형)1; 유형: CL111-철근콘크리트구조 기둥 (각형)_800x800_B2-4C1; 유형 ID: 7669456; 패밀리 및 유형: CL111-철근콘크리트구조 기둥 (각형)1: CL111-철근콘크리트구조 기둥 (각형)_800x800_B2-4C1
치수 - 길이: 6100 mm; 단면적: 0.64 m2; 체적: 3.07767 m3

# IfcColumn: CL111-철근콘크리트구조 기둥 (각형)1:CL111-철근콘크리트구조 기둥 (각형)_800x800_B2-7C3 (28)
Type - PredefinedType: COLUMN; Material: KBIMS-콘크리트
Type - ID 데이터 - 유형 마크: C3; 유형 이름: CL111-철근콘크리트구조 기둥 (각형)_800x800_B2-7C3
Type - 구조 - 단면 모양: 0
Type - 기타 - 내화구조여부: yes; 주요구조부여부: yes; 카테고리: 구조 기둥; KBIMS-부위코드: E22; 제작정보: bSK-2021_KBIMS2.0-bC; 조달청표준공사코드: AD; 패밀리 이름: CL111-철근콘크리트구조 기둥 (각형)1
Type - 재료 및 마감재 - 구조 재료: KBIMS-콘크리트
Type - 치수 - 가로치수: 800 mm; 세로치수: 800 mm
Type - Pset_ColumnCommon - IsExternal: no; LoadBearing: yes
Pset_ColumnCommon - Reference: CL111-철근콘크리트구조 기둥 (각형)_800x800_B2-7C3
Pset_QuantityTakeOff - Reference: CL111-철근콘크리트구조 기둥 (각형)_800x800_B2-7C3; sets with these values: 2
ID 데이터 - 연관 있음: no
공정 - 생성 공정: 새 구성
구속조건 - 베이스 간격띄우기: 0 mm; 룸 경계: yes; 상단 간격띄우기: 0 mm; 그리드와 함께 이동: yes; 기둥 스타일: 수직
구조 - 보강 철근 피복 - 다른 면: 보강 철근 피복 1 <25 mm>
기타 - 유형: CL111-철근콘크리트구조 기둥 (각형)_800x800_B2-7C3; 유형 ID: 7669459; 패밀리: CL111-철근콘크리트구조 기둥 (각형)1; 패밀리 및 유형: CL111-철근콘크리트구조 기둥 (각형)1: CL111-철근콘크리트구조 기둥 (각형)_800x800_B2-7C3
치수 - 단면적: 0.64 m2
Name (CL111-철근콘크리트구조 기둥 (각형)1:CL111-철근콘크리트구조 기둥 (각형)_800x800_B2-7C3:...) | In | Length (mm) | CrossSectionArea (m2) | OuterSurfaceArea (m2) | GrossVolume (m3) = NetVolume (m3) = 체적 (m3) | 레벨 = 베이스 레벨 | 기둥 위치 마크 | 상단 레벨 | 길이 (mm)
7668102 | 지하2층 | 3850 | 0.64 | 12.32 | 2.464 | 지하2층 | X1-Y1 | 지하1층 | 4000 | 구조 - 보강 철근 피복 - 하단 면: 보강 철근 피복 1 <25 mm>
7668106 | 지하2층 | 3850 | 0.64 | 12.32 | 2.464 | 지하2층 | X5-Y1 | 지하1층 | 4000 | 구조 - 보강 철근 피복 - 하단 면: 보강 철근 피복 1 <25 mm>
7668125 | 지하2층 | 3800 | 0.319972 | 9.11973 | 1.21589 | 지하2층 | X1-Y5 | 지하1층 | 4000 | 구조 - 보강 철근 피복 - 하단 면: 보강 철근 피복 1 <25 mm>
7668130 | 지상 1층 | 4650 | 0.64 | 14.88 | 2.976 | 지상 1층 | X1-Y1 | 지상 2층 | 4800
7668134 | 지상 1층 | 4650 | 0.64 | 14.88 | 2.976 | 지상 1층 | X5-Y1 | 지상 2층 | 4800
7668148 | 지상 1층 | 4650 | 0.64 | 14.88 | 2.976 | 지상 1층 | X1-Y5 | 지상 2층 | 4800
7668156 | 지하2층 | 1800 | 0.32 | 4.32 | 0.576 | PIT | X1-Y5 | 지하2층 | 1800 | 구조 - 보강 철근 피복 - 하단 면: 보강 철근 피복 1 <25 mm>; 보강 철근 피복 - 상단 면: 보강 철근 피복 1 <25 mm>
7668227 | 지하1층 | 5950 | 0.64 | 19.04 | 3.808 | 지하1층 | X1-Y1 | 지상 1층 | 6100
7668232 | 지하1층 | 5950 | 0.64 | 19.04 | 3.808 | 지하1층 | X5-Y1 | 지상 1층 | 6100
7668252 | 지하1층 | 5950 | 0.32 | 14.28 | 1.904 | 지하1층 | X1-Y5 | 지상 1층 | 6100
7668452 | 지상 2층 | 4350 | 0.64 | 13.92 | 2.784 | 지상 2층 | X1-Y1 | 지상 3층 | 4500
7668456 | 지상 2층 | 4350 | 0.64 | 13.92 | 2.784 | 지상 2층 | X5-Y1 | 지상 3층 | 4500
7668470 | 지상 2층 | 4350 | 0.64 | 13.92 | 2.784 | 지상 2층 | X1-Y5 | 지상 3층 | 4500
7668473 | 지상 3층 | 3950 | 0.64 | 12.64 | 2.528 | 지상 3층 | X1-Y1 | 지상 4층 | 4100
7668477 | 지상 3층 | 3950 | 0.64 | 12.64 | 2.528 | 지상 3층 | X5-Y1 | 지상 4층 | 4100
7668491 | 지상 3층 | 3950 | 0.64 | 12.64 | 2.528 | 지상 3층 | X1-Y5 | 지상 4층 | 4100 | Pset_ColumnCommon - Slope: 0 deg
7668494 | 지상 4층 | 3950 | 0.64 | 12.64 | 2.528 | 지상 4층 | X1-Y1 | 지상 5층 | 4100
7668498 | 지상 4층 | 3950 | 0.64 | 12.64 | 2.528 | 지상 4층 | X5-Y1 | 지상 5층 | 4100
7668512 | 지상 4층 | 3950 | 0.64 | 12.64 | 2.528 | 지상 4층 | X1-Y5 | 지상 5층 | 4100
7668515 | 지상 5층 | 3950 | 0.64 | 12.64 | 2.528 | 지상 5층 | X1-Y1 | 지상 6층 | 4100
7668519 | 지상 5층 | 3950 | 0.64 | 12.64 | 2.528 | 지상 5층 | X5-Y1 | 지상 6층 | 4100
7668533 | 지상 5층 | 3950 | 0.64 | 12.64 | 2.528 | 지상 5층 | X1-Y5 | 지상 6층 | 4100
7668536 | 지상 6층 | 3950 | 0.64 | 12.64 | 2.528 | 지상 6층 | X1-Y1 | 지상 7층 | 4100
7668540 | 지상 6층 | 3950 | 0.64 | 12.64 | 2.528 | 지상 6층 | X5-Y1 | 지상 7층 | 4100
7668554 | 지상 6층 | 3950 | 0.64 | 12.64 | 2.528 | 지상 6층 | X1-Y5 | 지상 7층 | 4100
7668557 | 지상 7층 | 3950 | 0.64 | 12.64 | 2.528 | 지상 7층 | X1-Y1 | 지상 8층 | 4100
7668561 | 지상 7층 | 3950 | 0.64 | 12.64 | 2.528 | 지상 7층 | X5-Y1 | 지상 8층 | 4100
7668575 | 지상 7층 | 3950 | 0.64 | 12.64 | 2.528 | 지상 7층 | X1-Y5 | 지상 8층 | 4100

# IfcColumn: CL111-철근콘크리트구조 기둥 (각형)1:CL111-철근콘크리트구조 기둥 (각형)_800x900_B2-1C2 (39)
Type - PredefinedType: COLUMN; Material: KBIMS-콘크리트
Type - ID 데이터 - 유형 마크: C2; 유형 이름: CL111-철근콘크리트구조 기둥 (각형)_800x900_B2-1C2
Type - 구조 - 단면 모양: 0
Type - 기타 - 내화구조여부: yes; 주요구조부여부: yes; 카테고리: 구조 기둥; KBIMS-부위코드: E22; 제작정보: bSK-2021_KBIMS2.0-bC; 조달청표준공사코드: AD; 패밀리 이름: CL111-철근콘크리트구조 기둥 (각형)1
Type - 재료 및 마감재 - 구조 재료: KBIMS-콘크리트
Type - 치수 - 가로치수: 800 mm; 세로치수: 900 mm
Type - Pset_ColumnCommon - IsExternal: no; LoadBearing: yes
Pset_ColumnCommon - Reference: CL111-철근콘크리트구조 기둥 (각형)_800x900_B2-1C2
Pset_QuantityTakeOff - Reference: CL111-철근콘크리트구조 기둥 (각형)_800x900_B2-1C2; sets with these values: 2
ID 데이터 - 연관 있음: no
공정 - 생성 공정: 새 구성
구속조건 - 베이스 간격띄우기: 0 mm; 상단 간격띄우기: 0 mm; 기둥 스타일: 수직
구조 - 보강 철근 피복 - 다른 면: 보강 철근 피복 1 <25 mm>
기타 - 패밀리: CL111-철근콘크리트구조 기둥 (각형)1; 유형: CL111-철근콘크리트구조 기둥 (각형)_800x900_B2-1C2; 유형 ID: 7669457; 패밀리 및 유형: CL111-철근콘크리트구조 기둥 (각형)1: CL111-철근콘크리트구조 기둥 (각형)_800x900_B2-1C2
치수 - 단면적: 0.72 m2
Name (CL111-철근콘크리트구조 기둥 (각형)1:CL111-철근콘크리트구조 기둥 (각형)_800x900_B2-1C2:...) | In | Length (mm) | CrossSectionArea (m2) | OuterSurfaceArea (m2) | GrossVolume (m3) | NetVolume (m3) = 체적 (m3) | 레벨 = 베이스 레벨 | 룸 경계 | 그리드와 함께 이동 | 상단 레벨 | 기둥 위치 마크 | 보강 철근 피복 - 하단 면 | 길이 (mm) | 보강 철근 피복 - 상단 면
7668103 | 지하2층 | 3850 | 0.72 | 13.09 | 2.772 | 2.772 | 지하2층 | yes | yes | 지하1층 | X2-Y1 | 보강 철근 피복 1 <25 mm> | 4000
7668104 | 지하2층 | 3850 | 0.72 | 13.09 | 2.772 | 2.772 | 지하2층 | yes | no | 지하1층 | X3-Y1 | 보강 철근 피복 1 <25 mm> | 4000
7668105 | 지하2층 | 3850 | 0.72 | 13.09 | 2.772 | 2.772 | 지하2층 | yes | yes | 지하1층 | X4-Y1 | 보강 철근 피복 1 <25 mm> | 4000
7668110 | 지하2층 |  | 7.32364 |  |  | 2.75533 | 지하2층 | yes | yes | 지하1층 | X1-Y2 | 보강 철근 피복 1 <25 mm> | 4000 | 보강 철근 피복 1 <25 mm>
7668111 | 지하2층 |  | 7.3025 |  |  | 2.7735 | 지하2층 | yes | yes | 지하1층 | X2-Y2 | 보강 철근 피복 1 <25 mm> | 4000 | 보강 철근 피복 1 <25 mm>
7668112 | 지하2층 | 3850 | 0.72 | 13.09 | 2.772 | 2.772 | 지하2층 | yes | yes | 지하1층 | X3-Y2 | 보강 철근 피복 1 <25 mm> | 4000 | 보강 철근 피복 1 <25 mm>
7668113 | 지하2층 | 3850 | 0.72 | 13.09 | 2.772 | 2.772 | 지하2층 | yes | yes | 지하1층 | X4-Y2 | 보강 철근 피복 1 <25 mm> | 4000 | 보강 철근 피복 1 <25 mm> | Pset_ColumnCommon - Slope: 0 deg
7668114 | 지하2층 | 3850 | 0.72 | 13.09 | 2.772 | 2.772 | 지하2층 | yes | yes | 지하1층 | X5-Y2 | 보강 철근 피복 1 <25 mm> | 4000 | 보강 철근 피복 1 <25 mm>
7668115 | 지하2층 | 3800 | 0.72 | 12.92 | 2.736 | 2.736 | 지하2층 | no | yes | 지하1층 | X1-Y3 | 보강 철근 피복 1 <25 mm> | 4000 | 보강 철근 피복 1 <25 mm> | Pset_ColumnCommon - Slope: 0 deg
7668117 | 지하2층 | 3850 | 0.72 | 13.09 | 2.772 | 2.772 | 지하2층 | yes | yes | 지하1층 | X2-Y3 | 보강 철근 피복 1 <25 mm> | 4000 | 보강 철근 피복 1 <25 mm>
7668120 | 지하2층 | 3800 | 0.54 | 11.4 | 2.052 | 2.052 | 지하2층 | yes | yes | 지하1층 | X1-Y4 | 보강 철근 피복 1 <25 mm> | 4000 | Pset_ColumnCommon - Slope: 0 deg
7668126 | 지하2층 | 4000 | 0.0440133 | 5.40241 | 0.176053 | 0.176053 | 지하2층 | yes | yes | 지하1층 | X2-Y5 | 보강 철근 피복 1 <25 mm> | 4000 | 보강 철근 피복 1 <25 mm> | Pset_ColumnCommon - Slope: 0 deg
7668131 | 지상 1층 | 4650 | 0.72 | 15.81 | 3.348 | 3.348 | 지상 1층 | yes | yes | 지상 2층 | X2-Y1 |  | 4800 | Pset_ColumnCommon - Slope: 0 deg
7668132 | 지상 1층 | 4650 | 0.72 | 15.81 | 3.348 | 3.348 | 지상 1층 | yes | yes | 지상 2층 | X3-Y1 |  | 4800 | 보강 철근 피복 1 <25 mm>
7668133 | 지상 1층 | 4650 | 0.72 | 15.81 | 3.348 | 3.348 | 지상 1층 | yes | yes | 지상 2층 | X4-Y1 | 보강 철근 피복 1 <25 mm> | 4800
7668135 | 지상 1층 | 4650 | 0.72 | 15.81 | 3.348 | 3.348 | 지상 1층 | yes | yes | 지상 2층 | X1-Y2 | 보강 철근 피복 1 <25 mm> | 4800
7668136 | 지상 1층 | 4650 | 0.72 | 15.81 | 3.348 | 3.348 | 지상 1층 | yes | yes | 지상 2층 | X2-Y2 | 보강 철근 피복 1 <25 mm> | 4800 | 보강 철근 피복 1 <25 mm>
7668137 | 지상 1층 | 4650 | 0.72 | 15.81 | 3.348 | 3.348 | 지상 1층 | yes | yes | 지상 2층 | X3-Y2 |  | 4800 | 보강 철근 피복 1 <25 mm>
7668138 | 지상 1층 | 4650 | 0.72 | 15.81 | 3.348 | 3.348 | 지상 1층 | yes | yes | 지상 2층 | X4-Y2 | 보강 철근 피복 1 <25 mm> | 4800
7668139 | 지상 1층 | 4650 | 0.72 | 15.81 | 3.348 | 3.348 | 지상 1층 | yes | yes | 지상 2층 | X5-Y2 |  | 4800
7668140 | 지상 1층 | 4650 | 0.72 | 15.81 | 3.348 | 3.348 | 지상 1층 | yes | yes | 지상 2층 | X1-Y3 |  | 4800
7668141 | 지상 1층 | 4650 | 0.72 | 15.81 | 3.348 | 3.348 | 지상 1층 | yes | yes | 지상 2층 | X2-Y3 |  | 4800 | 보강 철근 피복 1 <25 mm> | Pset_ColumnCommon - Slope: 0 deg
7668144 | 지상 1층 | 4650 | 0.72 | 15.81 | 3.348 | 3.348 | 지상 1층 | yes | yes | 지상 2층 | X1-Y4 | 보강 철근 피복 1 <25 mm> | 4800
7668145 | 지상 1층 | 4650 | 0.72 | 15.81 | 3.348 | 3.348 | 지상 1층 | yes | yes | 지상 2층 | X2-Y4 | 보강 철근 피복 1 <25 mm> | 4800 | 보강 철근 피복 1 <25 mm> | Pset_ColumnCommon - Slope: 0 deg
7668149 | 지상 1층 | 4650 | 0.54 | 13.95 | 2.511 | 2.511 | 지상 1층 | yes | yes | 지상 2층 | X2-Y5 |  | 4800 | 보강 철근 피복 1 <25 mm>
7668152 | 지하2층 | 1800 | 0.72 | 6.12 | 1.296 | 1.296 | PIT | yes | yes | 지하2층 | X1-Y3 | 보강 철근 피복 1 <25 mm> | 1800 | 보강 철근 피복 1 <25 mm>
7668154 | 지하2층 | 1800 | 0.54 | 5.4 | 0.971999 | 0.971999 | PIT | yes | yes | 지하2층 | X1-Y4 | 보강 철근 피복 1 <25 mm> | 1800 | 보강 철근 피복 1 <25 mm>
7668229 | 지하1층 | 5950 | 0.72 | 20.23 | 4.284 | 4.284 | 지하1층 | yes | yes | 지상 1층 | X2-Y1 |  | 6100
7668230 | 지하1층 | 5950 | 0.72 | 20.23 | 4.284 | 4.284 | 지하1층 | yes | yes | 지상 1층 | X3-Y1 |  | 6100
7668231 | 지하1층 | 5950 | 0.72 | 20.23 | 4.284 | 4.284 | 지하1층 | yes | yes | 지상 1층 | X4-Y1 |  | 6100 | 보강 철근 피복 1 <25 mm>
7668237 | 지하1층 | 5950 | 0.72 | 20.23 | 4.284 | 4.284 | 지하1층 | yes | yes | 지상 1층 | X1-Y2 | 보강 철근 피복 1 <25 mm> | 6100 | 보강 철근 피복 1 <25 mm>
7668238 | 지하1층 | 5950 | 0.72 | 20.23 | 4.284 | 4.284 | 지하1층 | yes | yes | 지상 1층 | X2-Y2 | 보강 철근 피복 1 <25 mm> | 6100 | 보강 철근 피복 1 <25 mm>
7668239 | 지하1층 | 5950 | 0.72 | 20.23 | 4.284 | 4.284 | 지하1층 | yes | yes | 지상 1층 | X3-Y2 | 보강 철근 피복 1 <25 mm> | 6100
7668240 | 지하1층 | 5950 | 0.72 | 20.23 | 4.284 | 4.284 | 지하1층 | yes | yes | 지상 1층 | X4-Y2 | 보강 철근 피복 1 <25 mm> | 6100 | 보강 철근 피복 1 <25 mm>
7668241 | 지하1층 | 5950 | 0.72 | 20.23 | 4.284 | 4.284 | 지하1층 | yes | yes | 지상 1층 | X5-Y2 | 보강 철근 피복 1 <25 mm> | 6100
7668242 | 지하1층 | 5950 | 0.72 | 20.23 | 4.284 | 4.284 | 지하1층 | yes | yes | 지상 1층 | X1-Y3 | 보강 철근 피복 1 <25 mm> | 6100
7668244 | 지하1층 | 5950 | 0.72 | 20.23 | 4.284 | 4.284 | 지하1층 | yes | yes | 지상 1층 | X2-Y3 | 보강 철근 피복 1 <25 mm> | 6100
7668247 | 지하1층 | 5950 | 0.72 | 20.23 | 4.284 | 4.284 | 지하1층 | yes | yes | 지상 1층 | X1-Y4 |  | 6100 | 보강 철근 피복 1 <25 mm>
7668253 | 지하1층 | 5950 | 0.0500348 | 8.03775 | 0.297707 | 0.297707 | 지하1층 | yes | yes | 지상 1층 | X2-Y5 | 보강 철근 피복 1 <25 mm> | 6100

# IfcColumn: CL111-철근콘크리트구조 기둥 (각형)1:CL111-철근콘크리트구조 기둥 (각형)_800x900_B2-1C2, CL111-철근콘크리트구조 기둥 (각형)1:CL111-철근콘크리트구조 기둥 (각형)_800x900_B2-1C2:7668122
In: 지하2층
Type - PredefinedType: COLUMN; Material: KBIMS-콘크리트 (2)
Type - ID 데이터 - 유형 마크: C2; 유형 이름: CL111-철근콘크리트구조 기둥 (각형)_800x900_B2-1C2
Type - 구조 - 단면 모양: 0
Type - 기타 - 내화구조여부: yes; 주요구조부여부: yes; 카테고리: 구조 기둥; KBIMS-부위코드: E22; 제작정보: bSK-2021_KBIMS2.0-bC; 조달청표준공사코드: AD; 패밀리 이름: CL111-철근콘크리트구조 기둥 (각형)1
Type - 재료 및 마감재 - 구조 재료: KBIMS-콘크리트
Type - 치수 - 가로치수: 800 mm; 세로치수: 900 mm
Type - Pset_ColumnCommon - IsExternal: no; LoadBearing: yes
BaseQuantities - Length: 3850 mm; CrossSectionArea: 0.277749 m2; OuterSurfaceArea: 9.54171 m2; GrossVolume: 1.06933 m3; NetVolume: 1.08371 m3
Pset_ColumnCommon - Slope: 0 deg; Reference: CL111-철근콘크리트구조 기둥 (각형)_800x900_B2-1C2
Pset_QuantityTakeOff - Reference: CL111-철근콘크리트구조 기둥 (각형)_800x900_B2-1C2; sets with these values: 2
ID 데이터 - 연관 있음: no
공정 - 생성 공정: 새 구성
구속조건 - 베이스 간격띄우기: 0 mm; 레벨: 지하2층; 룸 경계: yes; 상단 간격띄우기: 0 mm; 그리드와 함께 이동: yes; 기둥 스타일: 수직; 베이스 레벨: 지하2층; 상단 레벨: 지하1층; 기둥 위치 마크: X2-Y4
구조 - 보강 철근 피복 - 다른 면: 보강 철근 피복 1 <25 mm>; 보강 철근 피복 - 상단 면: 보강 철근 피복 1 <25 mm>; 보강 철근 피복 - 하단 면: 보강 철근 피복 1 <25 mm>
기타 - 패밀리: CL111-철근콘크리트구조 기둥 (각형)1; 유형: CL111-철근콘크리트구조 기둥 (각형)_800x900_B2-1C2; 유형 ID: 7669457; 패밀리 및 유형: CL111-철근콘크리트구조 기둥 (각형)1: CL111-철근콘크리트구조 기둥 (각형)_800x900_B2-1C2
치수 - 길이: 4000 mm; 단면적: 0.72 m2; 체적: 1.08371 m3

# IfcColumn: CL111-철근콘크리트구조 기둥 (각형)1:CL111-철근콘크리트구조 기둥 (각형)_800x900_B2-1C2, CL111-철근콘크리트구조 기둥 (각형)1:CL111-철근콘크리트구조 기둥 (각형)_800x900_B2-1C2:7668249
In: 지하1층
Type - PredefinedType: COLUMN; Material: KBIMS-콘크리트 (3)
Type - ID 데이터 - 유형 마크: C2; 유형 이름: CL111-철근콘크리트구조 기둥 (각형)_800x900_B2-1C2
Type - 구조 - 단면 모양: 0
Type - 기타 - 내화구조여부: yes; 주요구조부여부: yes; 카테고리: 구조 기둥; KBIMS-부위코드: E22; 제작정보: bSK-2021_KBIMS2.0-bC; 조달청표준공사코드: AD; 패밀리 이름: CL111-철근콘크리트구조 기둥 (각형)1
Type - 재료 및 마감재 - 구조 재료: KBIMS-콘크리트
Type - 치수 - 가로치수: 800 mm; 세로치수: 900 mm
Type - Pset_ColumnCommon - IsExternal: no; LoadBearing: yes
BaseQuantities - Length: 5950 mm; CrossSectionArea: 0.277749 m2; OuterSurfaceArea: 14.7463 m2; GrossVolume: 1.65261 m3; NetVolume: 1.67454 m3
Pset_ColumnCommon - Slope: 0 deg; Reference: CL111-철근콘크리트구조 기둥 (각형)_800x900_B2-1C2
Pset_QuantityTakeOff - Reference: CL111-철근콘크리트구조 기둥 (각형)_800x900_B2-1C2; sets with these values: 2
ID 데이터 - 연관 있음: no
공정 - 생성 공정: 새 구성
구속조건 - 베이스 간격띄우기: 0 mm; 레벨: 지하1층; 룸 경계: yes; 상단 간격띄우기: 0 mm; 그리드와 함께 이동: yes; 기둥 스타일: 수직; 베이스 레벨: 지하1층; 상단 레벨: 지상 1층; 기둥 위치 마크: X2-Y4
구조 - 보강 철근 피복 - 다른 면: 보강 철근 피복 1 <25 mm>; 보강 철근 피복 - 상단 면: 보강 철근 피복 1 <25 mm>; 보강 철근 피복 - 하단 면: 보강 철근 피복 1 <25 mm>
기타 - 패밀리: CL111-철근콘크리트구조 기둥 (각형)1; 유형: CL111-철근콘크리트구조 기둥 (각형)_800x900_B2-1C2; 유형 ID: 7669457; 패밀리 및 유형: CL111-철근콘크리트구조 기둥 (각형)1: CL111-철근콘크리트구조 기둥 (각형)_800x900_B2-1C2
치수 - 길이: 6100 mm; 단면적: 0.72 m2; 체적: 1.67454 m3

# IfcColumn: CL121-철골구조 기둥:CL121-철골구조 기둥_H-200x200x8x12_SC11 (21)
In: 옥탑층
Type - PredefinedType: COLUMN; Material: KBIMS-철골 구조
Type - ID 데이터 - 유형 마크: C11; 유형 이름: CL121-철골구조 기둥_H-200x200x8x12_SC11
Type - 구조 - 단면 모양: 0
Type - 기타 - 내화구조여부: yes; 주요구조부여부: yes; 카테고리: 구조 기둥; KBIMS-부위코드: E22; 제작정보: bSK-2021_KBIMS2.0-bC; 조달청표준공사코드: AEA; 패밀리 이름: CL121-철골구조 기둥
Type - 재료 및 마감재 - 구조 재료: KBIMS-철골 구조
Type - 치수 - 곡률반지름: 10 mm; 단면적: 109.898 m2; 단위무게: 86.2702 m2; 웨브두께: 6 mm; 웨브폭: 500 mm; 플랜지두께: 8 mm; 플랜지폭: 500 mm
Type - Pset_ColumnCommon - IsExternal: no; LoadBearing: yes
BaseQuantities - Length: 3660 mm; CrossSectionArea: 0.0109904 m2; OuterSurfaceArea: 10.8732 m2; GrossVolume: 0.040225 m3
Pset_ColumnCommon - Reference: CL121-철골구조 기둥_H-200x200x8x12_SC11
Pset_QuantityTakeOff - Reference: CL121-철골구조 기둥_H-200x200x8x12_SC11; sets with these values: 2
ID 데이터 - 연관 있음: no
공정 - 생성 공정: 새 구성
구속조건 - 레벨: 옥탑층; 그리드와 함께 이동: yes; 기둥 스타일: 수직; 베이스 간격띄우기: 740 mm; 베이스 레벨: 옥탑층; 상단 간격띄우기: 400 mm; 상단 레벨: 지붕층
기타 - 유형: CL121-철골구조 기둥_H-200x200x8x12_SC11; 유형 ID: 7669406; 패밀리: CL121-철골구조 기둥; 패밀리 및 유형: CL121-철골구조 기둥: CL121-철골구조 기둥_H-200x200x8x12_SC11
치수 - 길이: 3660 mm; 체적: 0.0399086 m3
Name (CL121-철골구조 기둥:CL121-철골구조 기둥_H-200x200x8x12_SC11:...) | 기둥 위치 마크
7669115 | X1(1,000)-Y5 | BaseQuantities - NetVolume: 0.0402234 m3
7669117 | X1(1,000)-Y4(2,000)
7669119 | X1(1,000)-Y4(-3,600)
7669121 | X1(1,000)-Y3(-1,200)
7669123 | X1(1,000)-Y2
7669125 | X1(1,000)-Y2(-5,700)
7669127 | X1(1,000)-Y1(1,000)
7669129 | X1(6,099)-Y1(1,000)
7669131 | X2(-2,201)-Y1(1,000)
7669133 | X3-Y1(1,000)
7669135 | X3(5,099)-Y1(1,000)
7669137 | X4(-601)-Y1(1,000)
7669139 | X4(4,399)-Y1(1,000)
7669141 | X5(-1,000)-Y1(1,000)
7669143 | X5(-1,000)-Y2(-5,840)
7669145 | X5(-1,000)-Y2(-380)
7669147 | X5(-1,000)-Y3(-1,620)
7669149 | X5(-1,000)-Y3(3,840)
7669151 | X5(-1,000)-Y4(1,300)
7669153 | X4(5,250)-Y4(1,300)
7669155 | X4(1,000)-Y4(1,300)

# IfcCovering: 복합 천장:A1-44-11A-경량철골천장틀(M-Bar), 무석면텍스 (7mm) (50)
Type - PredefinedType: CEILING
Type - ID 데이터 - 단가: 0; 유형 이름: A1-44-11A-경량철골천장틀(M-Bar), 무석면텍스 (7mm)
Type - 그래픽 - 거친 축척 채우기 색상: 0
Type - 기타 - 카테고리: 천장; KBIMS-부위코드: E36; 불연성재료: 불연재료; 조달청표준공사코드: AJI100100000+AOC12A; 패밀리 이름: 복합 천장
Type - 시공 - 두께: 7 mm
Type - 해석 특성 - 거칠기: 1; 열 저항(R): 0.105263; 열 전달 계수(U): 9.5 kg/K/s3; 열 질량: 2.3316; 흡수율: 30.48
Type - Pset_CoveringCommon - TotalThickness: 7 mm
Material: CE782-경량철골천장틀(M-Bar) 천장 1 mm, CE742-무석면텍스 천장 (시멘트계천장재) (6mm) 6 mm
Pset_CoveringCommon - Reference: A1-44-11A-경량철골천장틀(M-Bar), 무석면텍스 (7mm); Finish: CE742-무석면텍스 천장 (시멘트계천장재) (6mm);
Pset_QuantityTakeOff - Reference: A1-44-11A-경량철골천장틀(M-Bar), 무석면텍스 (7mm)
공정 - 생성 공정: 새 구성
구속조건 - 룸 경계: yes
기타 - 유형: A1-44-11A-경량철골천장틀(M-Bar), 무석면텍스 (7mm); 유형 ID: 6897900; 패밀리: 복합 천장; 패밀리 및 유형: 복합 천장: A1-44-11A-경량철골천장틀(M-Bar), 무석면텍스 (7mm)
Name (복합 천장:A1-44-11A-경량철골천장틀(M-Bar), 무석면텍스 (7mm):...) | In | GrossCeilingArea (m2) = 면적 (m2) | 레벨 | 레벨로부터 높이 간격띄우기 (mm) | 둘레 (mm) | 체적 (m3)
2980723 | 지상 2층 | 874.974 | 지상 2층 | 3180 | 331694 | 6.12482
2986122 | 190 | 97.902 | 지상 2층 | 3080 | 89707.9 | 0.685314
5459414 | 지상 3층 | 886.408 | 지상 3층 | 2980 | 205090 | 6.20485
5459499 | 204 | 98.0913 | 지상 3층 | 2680 | 89799.8 | 0.686639
5459565 | 지상 4층 | 932.925 | 지상 4층 | 2980 | 211336 | 6.53048
5459650 | 216 | 90.9737 | 지상 4층 | 2680 | 84017.7 | 0.636816
5465105 | 148 | 61.5576 | 지상 1층 | 3580 | 40871.4 | 0.430903
5465190 | 166 | 192.48 | 지상 1층 | 3630 | 136618 | 1.34736
5466796 | 149 | 50.1128 | 지상 1층 | 3580 | 34100 | 0.350789
5466862 | 150 | 52.4388 | 지상 1층 | 3580 | 34626.4 | 0.367072
5466951 | 151 | 52.3398 | 지상 1층 | 3580 | 34626.3 | 0.366379
5467474 | 153 | 52.5275 | 지상 1층 | 3580 | 34499.4 | 0.367693
5467496 | 154 | 53.2734 | 지상 1층 | 3580 | 34464.3 | 0.372914
5467510 | 155 | 52.0055 | 지상 1층 | 3580 | 34414.2 | 0.364038
5467623 | 156 | 67.6693 | 지상 1층 | 3580 | 35670 | 0.473685
5467660 | 157 | 65.0346 | 지상 1층 | 3580 | 35160 | 0.455242
5467753 | 158 | 39.3962 | 지상 1층 | 3580 | 28099.9 | 0.275773
5467808 | 159 | 40.6778 | 지상 1층 | 3580 | 28225 | 0.284744
5467828 | 160 | 39.625 | 지상 1층 | 3580 | 28150 | 0.277375
5467928 | 161 | 47.0958 | 지상 1층 | 3580 | 30025 | 0.32967
5467948 | 162 | 42.9262 | 지상 1층 | 3580 | 29024.9 | 0.300483
5467993 | 163 | 44.8854 | 지상 1층 | 3580 | 29550.1 | 0.314198
5468258 | 236 | 90.8003 | 지상 5층 | 2680 | 83999.7 | 0.635602
5468398 | 251 | 90.7767 | 지상 6층 | 2680 | 84007.7 | 0.635437
5468538 | 지상 7층 | 90.7767 | 지상 7층 | 2680 | 84007.7 | 0.635437
5468678 | 283 | 90.7767 | 지상 8층 | 2680 | 84007.7 | 0.635437
5468745 | 지상 9층 | 889.095 | 지상 9층 | 3080 | 202090 | 6.22367
5468830 | 294 | 97.9017 | 지상 9층 | 3080 | 89707.8 | 0.685312
5468897 | 308 | 97.9017 | 지상 10층 | 3580 | 89707.8 | 0.685312
5468932 | 지상 10층 | 886.312 | 지상 10층 | 3580 | 202024 | 6.20418
5471533 | 지상 5층 | 933.012 | 지상 5층 | 2980 | 211000 | 6.53108
5471631 | 지상 6층 | 933.328 | 지상 6층 | 2980 | 211070 | 6.5333
5471729 | 지상 7층 | 933.342 | 지상 7층 | 2980 | 234748 | 6.5334
5471827 | 지상 8층 | 935.603 | 지상 8층 | 2980 | 208270 | 6.54922
5876508 | 167 | 28.2252 | 지상 1층 | 3580 | 21694.9 | 0.197577
5876670 | 86 | 5.66248 | 지상 1층 | 3580 | 9529.98 | 0.0396373
5876783 | 172 | 10.856 | 지상 1층 | 3580 | 13800 | 0.0759919
6032609 | 169 | 6.93388 | 지상 1층 | 3580 | 10803.7 | 0.0485371
6032681 | 185 | 6.93002 | 지상 2층 | 3180 | 10800 | 0.0485101
6032903 | 201 | 6.93002 | 지상 3층 | 2980 | 10800 | 0.0485101
6033124 | 223 | 6.93002 | 지상 4층 | 2980 | 10800 | 0.0485101
6033325 | 224 | 6.93002 | 지상 5층 | 2980 | 10800 | 0.0485101
6033610 | 239 | 6.93002 | 지상 6층 | 2980 | 10800 | 0.0485101
6033809 | 265 | 6.93002 | 지상 7층 | 2980 | 10800 | 0.0485101
6034012 | 280 | 6.93002 | 지상 8층 | 2980 | 10800 | 0.0485101
6034210 | 293 | 6.93002 | 지상 9층 | 3080 | 10800 | 0.0485101
6034414 | 311 | 6.93002 | 지상 10층 | 3580 | 10800 | 0.0485101
6034613 | 옥탑층 | 6.75703 | 옥탑층 | 3000 | 10656 | 0.0472992
6034639 | 319 | 14.1947 | 옥탑층 | 3000 | 16161.7 | 0.0993626
6034654 | 옥탑층 | 12.8953 | 옥탑층 | 3000 | 16899.8 | 0.0902672

# IfcCovering: 복합 천장:A1-45-06A-경량철골천장틀(M-Bar), 열경화성수지(300x300x1.2mm) (2mm) TYPE-D (20)
Type - PredefinedType: CEILING
Type - ID 데이터 - 단가: 0; 유형 이름: A1-45-06A-경량철골천장틀(M-Bar), 열경화성수지(300x300x1.2mm) (2mm) TYPE-D
Type - 그래픽 - 거친 축척 채우기 색상: 0
Type - 기타 - 카테고리: 천장; KBIMS-부위코드: E36; 불연성재료: 불연재료; 조달청표준공사코드: AJI100100000+AOMB; 패밀리 이름: 복합 천장
Type - 시공 - 두께: 2 mm
Type - 해석 특성 - 거칠기: 1; 흡수율: 30.48
Type - Pset_CoveringCommon - TotalThickness: 2 mm
Material: CE782-경량철골천장틀(M-Bar) 천장 1 mm, CE761-열경화성수지 천장 (300x300x1.2mm) 1 mm
Pset_CoveringCommon - Reference: A1-45-06A-경량철골천장틀(M-Bar), 열경화성수지(300x300x1.2mm) (2mm) TYPE-D; Finish: CE761-열경화성수지 천장 (300x300x1.2mm);
Pset_QuantityTakeOff - Reference: A1-45-06A-경량철골천장틀(M-Bar), 열경화성수지(300x300x1.2mm) (2mm) TYPE-D
공정 - 생성 공정: 새 구성
구속조건 - 룸 경계: yes
기타 - 패밀리: 복합 천장; 유형: A1-45-06A-경량철골천장틀(M-Bar), 열경화성수지(300x300x1.2mm) (2mm) TYPE-D; 유형 ID: 6897901; 패밀리 및 유형: 복합 천장: A1-45-06A-경량철골천장틀(M-Bar), 열경화성수지(300x300x1.2mm) (2mm) TYPE-D
Name (복합 천장:A1-45-06A-경량철골천장틀(M-Bar), 열경화성수지(300x300x1.2mm) (2mm) TYPE-D:...) | In | GrossCeilingArea (m2) = 면적 (m2) | 레벨 | 레벨로부터 높이 간격띄우기 (mm) | 둘레 (mm) | 체적 (m3)
3148765 | 171 | 11.44 | 지상 1층 | 1690 | 14000 | 0.02288
7699153 | 170 | 16.8849 | 지상 1층 | 1690 | 21529.9 | 0.0337697
7704583 | 지상 2층 | 16.8849 | 지상 2층 | 2690 | 21529.9 | 0.0337697
7704638 | 지상 3층 | 16.8849 | 지상 3층 | 2690 | 21529.9 | 0.0337697
7704658 | 지상 4층 | 16.8849 | 지상 4층 | 2690 | 21529.9 | 0.0337697
7704678 | 지상 5층 | 16.8849 | 지상 5층 | 2690 | 21529.9 | 0.0337697
7704698 | 지상 6층 | 16.8849 | 지상 6층 | 2690 | 21529.9 | 0.0337697
7704718 | 지상 7층 | 16.8849 | 지상 7층 | 2690 | 21529.9 | 0.0337697
7704738 | 지상 8층 | 16.8849 | 지상 8층 | 2690 | 21529.9 | 0.0337697
7704758 | 지상 9층 | 16.8849 | 지상 9층 | 2690 | 21529.9 | 0.0337697
7704778 | 지상 10층 | 16.8849 | 지상 10층 | 2690 | 21529.9 | 0.0337697
7707099 | 지상 2층 | 11.44 | 지상 2층 | 2690 | 14000 | 0.02288
7707136 | 지상 3층 | 11.44 | 지상 3층 | 2690 | 14000 | 0.02288
7707152 | 지상 4층 | 11.44 | 지상 4층 | 2690 | 14000 | 0.02288
7707168 | 지상 5층 | 11.44 | 지상 5층 | 2690 | 14000 | 0.02288
7707184 | 지상 6층 | 11.44 | 지상 6층 | 2690 | 14000 | 0.02288
7707200 | 지상 7층 | 11.44 | 지상 7층 | 2690 | 14000 | 0.02288
7707216 | 지상 8층 | 11.44 | 지상 8층 | 2690 | 14000 | 0.02288
7707232 | 지상 9층 | 11.44 | 지상 9층 | 2690 | 14000 | 0.02288
7707248 | 지상 10층 | 11.44 | 지상 10층 | 2690 | 14000 | 0.02288

# IfcCovering: 복합 천장:A1-46-01B-콘크리트면정리, 유리면 흡음판(그라스크로스) (50mm) (4)
Type - PredefinedType: CEILING
Type - ID 데이터 - 단가: 0; 유형 이름: A1-46-01B-콘크리트면정리, 유리면 흡음판(그라스크로스) (50mm)
Type - 그래픽 - 거친 축척 채우기 색상: 0
Type - 기타 - 카테고리: 천장; KBIMS-부위코드: E36; 불연성재료: 불연재료; 조달청표준공사코드: ADR130400000+AOM20101A; 패밀리 이름: 복합 천장
Type - 시공 - 두께: 50 mm
Type - 해석 특성 - 거칠기: 1; 흡수율: 30.48
Type - Pset_CoveringCommon - TotalThickness: 50 mm
Material: CE554-콘크리트면정리 천장 1 mm, CE751-유리면 흡음판 천장 (48k, 그라스크로스, 50mm) 49 mm
Pset_CoveringCommon - Reference: A1-46-01B-콘크리트면정리, 유리면 흡음판(그라스크로스) (50mm); Finish: CE751-유리면 흡음판 천장 (48k, 그라스크로스, 50mm);
Pset_QuantityTakeOff - Reference: A1-46-01B-콘크리트면정리, 유리면 흡음판(그라스크로스) (50mm)
BaseQuantities - GrossCeilingArea: 36.835 m2
공정 - 생성 공정: 새 구성
구속조건 - 룸 경계: yes
기타 - 패밀리: 복합 천장; 유형: A1-46-01B-콘크리트면정리, 유리면 흡음판(그라스크로스) (50mm); 유형 ID: 6897902; 패밀리 및 유형: 복합 천장: A1-46-01B-콘크리트면정리, 유리면 흡음판(그라스크로스) (50mm)
치수 - 둘레: 26100 mm; 면적: 36.835 m2; 체적: 1.84175 m3
Name (복합 천장:A1-46-01B-콘크리트면정리, 유리면 흡음판(그라스크로스) (50mm):...) | In | 레벨 | 레벨로부터 높이 간격띄우기 (mm)
6544417 | 89 | 지상 10층 | 3580
6544860 | 87 | 지상 2층 | 3180
6544884 | 8 | 지상 3층 | 2980
6544908 | 88 | 지상 9층 | 3080

# IfcCurtainWall: 기본 벽:WA111-철근콘크리트구조 벽 100mm (26)
Type - Material: KBIMS-콘크리트 100 mm
Type - ID 데이터 - 단가: 0; 유형 이름: WA111-철근콘크리트구조 벽 100mm
Type - 그래픽 - 거친 축척 채우기 색상: 0
Type - 기타 - 카테고리: 벽; KBIMS-부위코드: E275; 조달청표준공사코드: AD; 패밀리 이름: 기본 벽
Type - 시공 - 기능: 외부; 끝단부 마무리: 없음; 인서트 부위 마무리: 마무리하지 않음; 폭: 100 mm
Type - 재료 및 마감재 - 구조 재료: KBIMS-콘크리트
Type - 해석 특성 - 거칠기: 1; 열 저항(R): 0.0956023; 열 전달 계수(U): 10.46 kg/K/s3; 열 질량: 151.11; 흡수율: 9290.3
Type - Pset_CurtainWallCommon - IsExternal: yes; ThermalTransmittance: 10.46 kg/K/s3
ID 데이터 - 다음으로 분류: 패널
공정 - 생성 공정: 새 구성
구속조건 - 매스와 관련됨: no; 베이스 확장 거리: 0 mm; 상단 확장 거리: 0 mm; 위치선: 벽 중심선; 위치선 간격띄우기: 0 mm
구조 - 구조: no; 구조적 용도: 비교좌장치
기타 - 패밀리: 기본 벽; 카테고리: 커튼월 패널; 유형: WA111-철근콘크리트구조 벽 100mm; 유형 ID: 7676586; 패밀리 및 유형: 기본 벽: WA111-철근콘크리트구조 벽 100mm
단면형상 정의 - 단면형상: 수직
Pset_CurtainWallCommon - Reference: WA111-철근콘크리트구조 벽 100mm
Pset_QuantityTakeOff - Reference: WA111-철근콘크리트구조 벽 100mm
Name (기본 벽:WA111-철근콘크리트구조 벽 100mm:...) | In | 베이스 구속조건 | 미연결 높이 (mm) = 높이 (mm) | 베이스 간격띄우기 (mm) | 길이 (mm) = 폭 (mm) | 면적 (m2) | 체적 (m3)
7688074 | 지상 1층 | 지상 1층 | 2075 | 80 | 950 | 0.00286592 | 0.000286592
7688075 | 지상 1층 | 지상 1층 | 2075 | 80 | 1074.98 | 0.285277 | 0.0285277
7688076 | 지상 1층 | 지상 1층 | 2075 | 80 | 1025.02 | 0.207536 | 0.0207536
7688077 | 지상 1층 | 지상 1층 | 2075 | 80 | 960 | 0.02075 | 0.002075
7681031 | 지상 1층 | 지상 1층 | 2075 | 80 | 1025 | 0.181562 | 0.0181562
7686028 | 지상 1층 | 지상 1층 | 2075 | 80 | 990 | 0.083 | 0.0083
7686357 | 지상 1층 | 지상 1층 | 2075 | 80 | 975.035 | 0.0519485 | 0.00519485
7687806 | 지상 1층 | 지상 1층 | 2075 | -420 | 1750 | 0.0110823 | 0.00110823
7686358 | 지상 1층 | 지상 1층 | 2075 | -420 | 1075 | 0.259375 | 0.0259375
7686359 | 지상 1층 | 지상 1층 | 2075 | -1420 | 974.965 | 0.0777407 | 0.00777407
7687809 | 지상 1층 | 지상 1층 | 2075 | -420 | 1750 | 0.0120546 | 0.00120546
7678814 | 지상 1층 | 지상 1층 | 2075 | 80 | 1750 | 0.0168264 | 0.00168264
7689660 | 지상 1층 | 지상 1층 | 2075 | 80 | 950 | 0.0257306 | 0.00257306
7695924 | 지상 3층 | 지상 3층 | 2075 | 80 | 1505 | 0.0103744 | 0.00103744
7727936 | 지상 3층 | 지상 3층 | 2075 | 80 | 310 | 0.64325 | 0.064325
7727939 | 지하2층 | 지하2층 | 2025 | 250 | 1750 | 3.54375 | 0.354375
7727940 | 지하1층 | 지하1층 | 2025 | 250 | 1750 | 3.54375 | 0.354375
7695931 | 지상 4층 | 지상 4층 | 2075 | 80 | 1450 | 0.000531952 | 0.0000531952
7695935 | 지상 9층 | 지상 9층 | 2075 | 80 | 5 | 0.010375 | 0.0010375
7695952 | 지상 4층 | 지상 4층 | 2075 | 80 | 5 | 0.010375 | 0.0010375
7695953 | 지상 5층 | 지상 5층 | 2075 | 80 | 5 | 0.010375 | 0.0010375
7695954 | 지상 6층 | 지상 6층 | 2075 | 80 | 5 | 0.010375 | 0.0010375
7695955 | 지상 7층 | 지상 7층 | 2075 | 80 | 5 | 0.010375 | 0.0010375
7695956 | 지상 8층 | 지상 8층 | 2075 | 80 | 5 | 0.010375 | 0.0010375
7695958 | 지상 10층 | 지상 10층 | 2075 | 80 | 5 | 0.010375 | 0.0010375
7690950 | 지상 2층 | 지상 2층 | 2075 | 80 | 1505 | 0.0103744 | 0.00103744

# IfcCurtainWall: 커튼월:CW112-스테인리스 스틸 커튼월 (156)
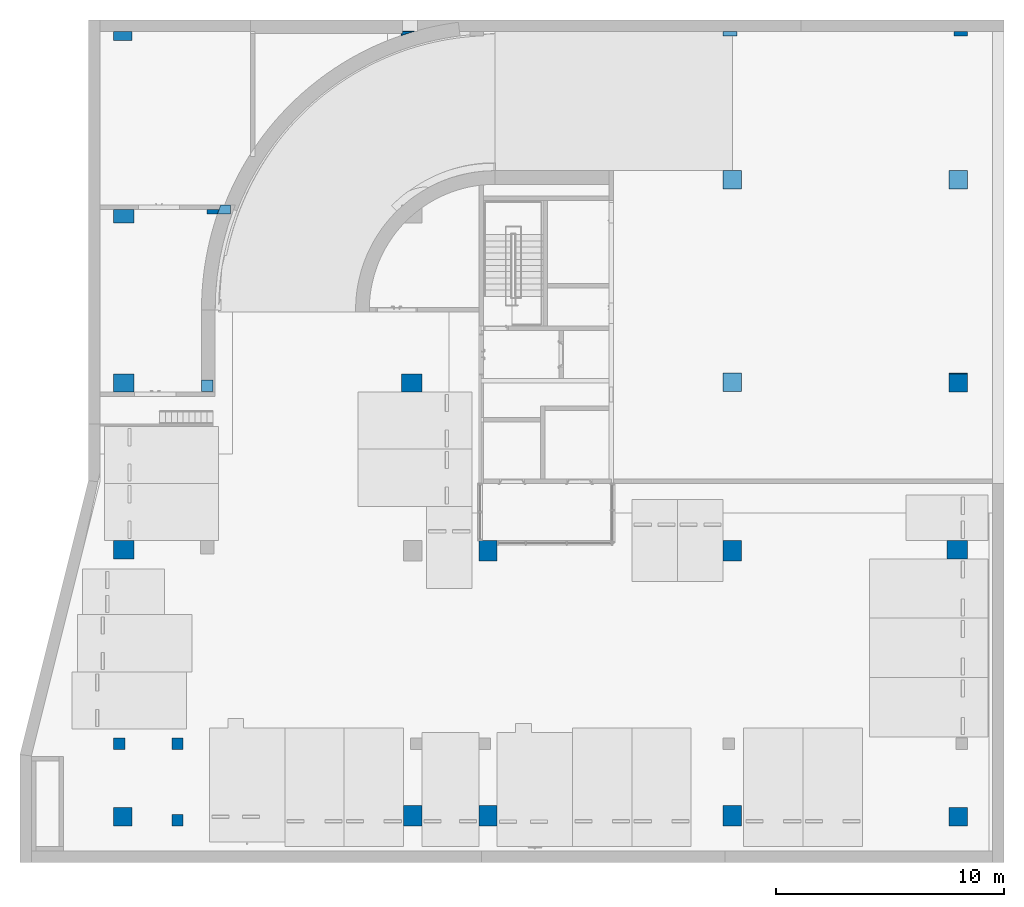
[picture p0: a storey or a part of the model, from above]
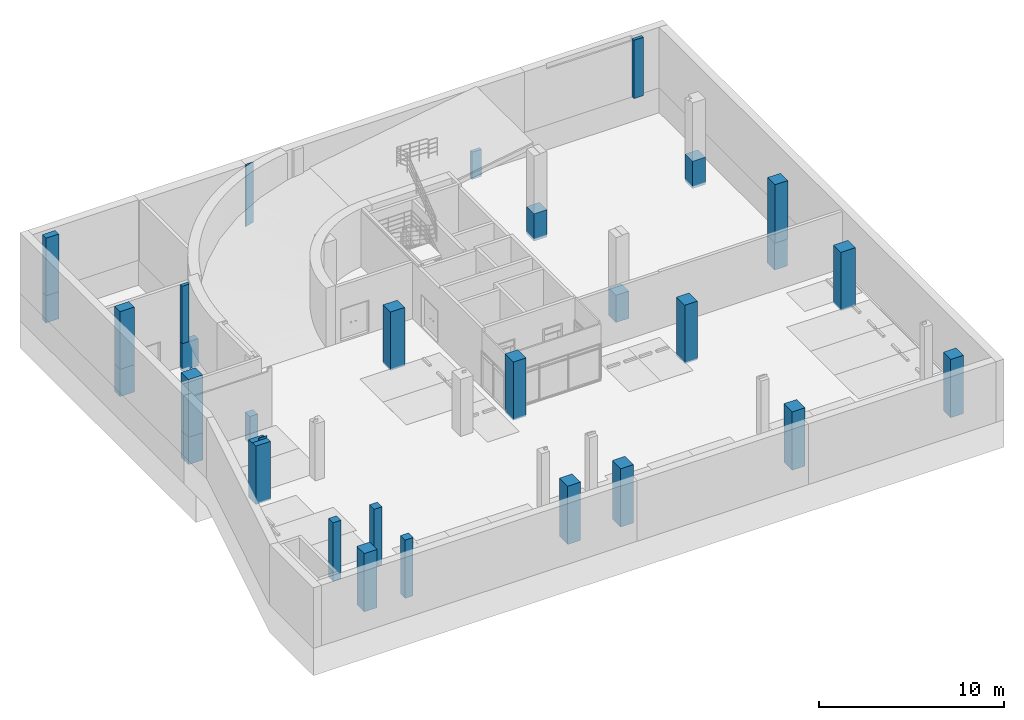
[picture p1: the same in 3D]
Properties of the parts of a building model (IFC2X3), part 11 of 39

# IfcCurtainWall: 커튼월:CW112-스테인리스 스틸 커튼월 (156)
Type - ID 데이터(Type) - 단가: 0; 유형 이름: CW112-스테인리스 스틸 커튼월
Type - 기타(Type) - 카테고리: 벽; KBIMS-부위코드: E336; 조달청표준공사코드: ALC1; 패밀리 이름: 커튼월
Type - 수직 그리드(Type) - 멀리언 크기 조정: no; 배치: 없음
Type - 수평 그리드(Type) - 멀리언 크기 조정: no; 배치: 없음
Type - 시공(Type) - 기능: 외부; 결합 조건: 정의 안 됨; 자동으로 내장: yes
Type - Pset_CurtainWallCommon - IsExternal: yes
Pset_CurtainWallCommon - Reference: CW112-스테인리스 스틸 커튼월
Pset_QuantityTakeOff - Reference: CW112-스테인리스 스틸 커튼월
공정 - 생성 공정: 새 구성
구속조건 - 매스와 관련됨: no; 룸 경계: yes; 벽 베이스가 부착됩니다.: no; 상단이 부착됩니다.: no
구조 - 구조: no; 구조적 용도: 비교좌장치
기타 - 카테고리: 벽; 유형: CW112-스테인리스 스틸 커튼월; 유형 ID: 7675291; 패밀리: 커튼월; 패밀리 및 유형: 커튼월: CW112-스테인리스 스틸 커튼월
단면형상 정의 - 단면형상: 수직
수직 그리드 - 각도: 0 deg; 간격띄우기: 0 mm; 맞춤: 시작; 번호: 4; sets with these values: 2
Name (커튼월:CW112-스테인리스 스틸 커튼월:...) | In | 마크 | 해설 | 베이스 구속조건 | 상단 구속조건 | 미연결 높이 (mm) | 베이스 간격띄우기 (mm) | 상단 간격띄우기 (mm) | 길이 (mm) | 면적 (m2)
2836336 | 지상 1층 | 2 | SSD | 지상 1층 | 상위 레벨: 지상 2층 | 3520 | 80 | -1200 | 7200.02 | 25.3441
2838631 | 지상 1층 | 3 | SSD | 지상 1층 | 상위 레벨: 지상 2층 | 3520 | 80 | -1200 | 6600 | 23.232
2839308 | 지상 1층 | 5 | SSD | 지상 1층 | 상위 레벨: 지상 2층 | 3520 | 80 | -1200 | 10900 | 38.3679
2842071 | 지상 1층 | 6 | SSD | 지상 1층 | 상위 레벨: 지상 2층 | 3520 | 80 | -1200 | 11900 | 41.888
2844131 | 지상 1층 | 8 | SSD | 지상 1층 | 상위 레벨: 지상 2층 | 3520 | 80 | -1200 | 9900 | 34.848
2844807 | 지상 1층 | 9 | SSD | 지상 1층 | 상위 레벨: 지상 2층 | 3520 | 80 | -1200 | 9082 | 31.9686
2847227 | 지상 1층 | 10 | SSD | 지상 1층 | 상위 레벨: 지상 2층 | 3520 | 80 | -1200 | 10900 | 38.3681
2850019 | 지상 1층 | 11 | SSD | 지상 1층 | 상위 레벨: 지상 2층 | 4020 | -420 | -1200 | 6540 | 26.2908
2851881 | 지상 1층 | 12 | SSD | 지상 1층 | 상위 레벨: 지상 2층 | 5020 | -1420 | -1200 | 7982 | 40.0696
2853669 | 지상 1층 | 13 | SSD | 지상 1층 | 상위 레벨: 지상 2층 | 2020 | -470 | -3250 | 1700 | 2.82798
2855064 | 지상 1층 | 14 | SSD | 지상 1층 | 상위 레벨: 지상 2층 | 3520 | 80 | -1200 | 1200 | 4.224
2855926 | 지상 1층 | 15 | SSD | 지상 1층 | 상위 레벨: 지상 2층 | 3520 | 80 | -1200 | 6568.72 | 22.8535
2857417 | 지상 1층 | 15 | SSD | 지상 1층 | 상위 레벨: 지상 2층 | 4020 | -420 | -1200 | 2600 | 10.05
2857502 | 지상 1층 | 15 | SSD | 지상 1층 | 상위 레벨: 지상 2층 | 3520 | 80 | -1200 | 2590.02 | 8.80006
2864007 | 지상 1층 | 18 | SSD | 지상 1층 | 상위 레벨: 지상 2층 | 3520 | 80 | -1200 | 9000 | 31.68
2865038 | 지상 1층 | 19 | SSD | 지상 1층 | 상위 레벨: 지상 2층 | 4800 | 0 | 0 | 7487.49 | 25.3077
2867553 | 지상 1층 | 20 | SSD | 지상 1층 | 상위 레벨: 지상 2층 | 3520 | 80 | -1200 | 10700 | 37.664
2870107 | 지상 1층 | 21 | SSD | 지상 1층 | 상위 레벨: 지상 2층 | 3520 | 80 | -1200 | 10700 | 37.664
2872001 | 지상 1층 | 22 | SSD | 지상 1층 | 상위 레벨: 지상 2층 | 3520 | 80 | -1200 | 9900 | 34.848
2874145 | 지상 1층 | 23 | SSD | 지상 1층 | 상위 레벨: 지상 2층 | 3520 | 80 | -1200 | 6599.98 | 23.2319
2875696 | 지상 1층 | 24 | SSD | 지상 1층 | 상위 레벨: 지상 2층 | 3520 | 80 | -1200 | 3929.98 | 13.8335
2875827 | 지상 1층 | 24 | SSD | 지상 1층 | 상위 레벨: 지상 2층 | 3520 | 80 | -1200 | 2693.15 | 9.1279
2880752 | 지상 2층 | 0 | AW | 지상 2층 | 상위 레벨: 지상 3층 | 3120 | 80 | -1300 | 1200 | 3.744
2894516 | 지상 2층 | 5 | AW | 지상 2층 | 상위 레벨: 지상 3층 | 3120 | 80 | -1300 | 7210 | 22.4952
2897084 | 지상 2층 | 6 | AW | 지상 2층 | 상위 레벨: 지상 3층 | 3120 | 80 | -1300 | 6600 | 20.592
2898536 | 지상 2층 | 7 | AW | 지상 2층 | 상위 레벨: 지상 3층 | 3120 | 80 | -1300 | 6500 | 20.28
2900183 | 지상 2층 | 8 | AW | 지상 2층 | 상위 레벨: 지상 3층 | 3120 | 80 | -1300 | 5366 | 16.7138
2901336 | 지상 2층 | 9 | AW | 지상 2층 | 상위 레벨: 지상 3층 | 3120 | 80 | -1300 | 4322.75 | 13.487
2902261 | 지상 2층 | 10 | AW | 지상 2층 | 상위 레벨: 지상 3층 | 3120 | 80 | -1300 | 5441.03 | 16.9479
2903630 | 지상 2층 | 11 | AW | 지상 2층 | 상위 레벨: 지상 3층 | 3120 | 80 | -1300 | 5450.11 | 17.0044
2904974 | 지상 2층 | 12 | AW | 지상 2층 | 상위 레벨: 지상 3층 | 3120 | 80 | -1300 | 2500 | 7.8
2905064 | 지상 2층 | 13 | AW | 지상 2층 | 상위 레벨: 지상 3층 | 3120 | 80 | -1300 | 4466.27 | 13.9067
2905217 | 지상 2층 | 14 | AW | 지상 2층 | 상위 레벨: 지상 3층 | 3120 | 80 | -1300 | 4449.82 | 13.8835
2905351 | 지상 2층 | 15 | AW | 지상 2층 | 상위 레벨: 지상 3층 | 3120 | 80 | -1300 | 4026.1 | 12.5614
2905462 | 지상 2층 | 16 | AW | 지상 2층 | 상위 레벨: 지상 3층 | 3120 | 80 | -1300 | 4048.16 | 12.6022
2905548 | 지상 2층 | 17 | AW | 지상 2층 | 상위 레벨: 지상 3층 | 3120 | 80 | -1300 | 4916 | 15.3098
2905633 | 지상 2층 | 18 | AW | 지상 2층 | 상위 레벨: 지상 3층 | 3120 | 80 | -1300 | 4916 | 15.3098
2905747 | 지상 2층 | 19 | AW | 지상 2층 | 상위 레벨: 지상 3층 | 3120 | 80 | -1300 | 6491 | 20.2238
2905902 | 지상 2층 | 20 | AW | 지상 2층 | 상위 레벨: 지상 3층 | 3120 | 80 | -1300 | 8100 | 25.272
2914928 | 지상 2층 | 21 | AW | 지상 2층 | 상위 레벨: 지상 3층 | 3120 | 80 | -1300 | 8970.43 | 27.9878
2917765 | 지상 3층 | 26 | SSD | 지상 3층 | 상위 레벨: 지상 4층 | 2620 | 80 | -1400 | 2850 | 7.205
2918211 | 지상 2층 | 26 | SSD | 지상 2층 | 상위 레벨: 지상 3층 | 3020 | 80 | -1400 | 6600 | 19.932
2918867 | 지상 3층 | 26 | SSD | 지상 3층 | 상위 레벨: 지상 4층 | 2620 | 80 | -1400 | 6600 | 17.292
2919133 | 지상 10층 | 26 | SSD | 지상 10층 | 상위 레벨: 옥탑층 | 3520 | 80 | -1400 | 6700 | 20.4715
2919261 | 지상 2층 | 27 | SSD | 지상 2층 | 상위 레벨: 지상 3층 | 3020 | 80 | -1400 | 6500 | 19.63
2919869 | 지상 9층 | 26 | SSD | 지상 9층 | 상위 레벨: 지상 10층 | 3020 | 80 | -1400 | 6800.03 | 17.4236
2920059 | 지상 9층 | 27 | SSD | 지상 9층 | 상위 레벨: 지상 10층 | 3020 | 80 | -1400 | 6500.03 | 16.5176
2920393 | 지상 4층 | 27 | SSD | 지상 4층 | 상위 레벨: 지상 5층 | 2620 | 80 | -1400 | 6500 | 13.9175
2920538 | 지상 10층 | 27 | SSD | 지상 10층 | 상위 레벨: 옥탑층 | 3520 | 80 | -1400 | 6549.28 | 19.765
2920611 | 지상 2층 | 25 | SSD | 지상 2층 | 상위 레벨: 지상 3층 | 3020 | 80 | -1400 | 2499.97 | 7.54992
2920734 | 지상 2층 | 28 | SSD | 지상 2층 | 상위 레벨: 지상 3층 | 3020 | 80 | -1400 | 9900 | 29.898
2921989 | 지상 3층 | 25 | SSD | 지상 3층 | 상위 레벨: 지상 4층 | 2620 | 80 | -1400 | 2499.99 | 3.43748
2922163 | 지상 9층 | 25 | SSD | 지상 9층 | 상위 레벨: 지상 10층 | 3020 | 80 | -1400 | 2500 | 4.4375
2922192 | 지상 10층 | 25 | SSD | 지상 10층 | 상위 레벨: 옥탑층 | 3520 | 80 | -1400 | 2500 | 5.6875
2923035 | 지상 3층 | 28 | SSD | 지상 3층 | 상위 레벨: 지상 4층 | 2620 | 80 | -1400 | 9900.02 | 22.8255
2923305 | 지상 9층 | 28 | SSD | 지상 9층 | 상위 레벨: 지상 10층 | 3020 | 80 | -1400 | 10000 | 27.0875
2923350 | 지상 10층 | 28 | SSD | 지상 10층 | 상위 레벨: 옥탑층 | 3520 | 80 | -1400 | 10000 | 32.0875
2923462 | 지상 2층 | 29 | SSD | 지상 2층 | 상위 레벨: 지상 3층 | 3020 | 80 | -1400 | 2218 | 6.69836
2923549 | 지상 2층 | 29 | SSD | 지상 2층 | 상위 레벨: 지상 3층 | 3020 | 80 | -1400 | 2720.98 | 8.21737
2923615 | 지상 2층 | 29 | SSD | 지상 2층 | 상위 레벨: 지상 3층 | 3020 | 80 | -1400 | 2818.01 | 8.51039
2926331 | 지상 3층 | 22 | AW | 지상 3층 | 상위 레벨: 지상 4층 | 2620 | 80 | -1400 | 2099.37 | 5.50034
2927264 | 지상 3층 | 23 | AW | 지상 3층 | 상위 레벨: 지상 4층 | 2620 | 80 | -1400 | 35400 | 92.748
2936724 | 지상 4층 | 23 | AW | 지상 4층 | 상위 레벨: 지상 5층 | 4100 | -1400 | -1400 | 11799.7 | 48.3789
2938145 | 지상 4층 | 23 | AW | 지상 4층 | 상위 레벨: 지상 5층 | 2100 | 600 | -1400 | 21810.4 | 45.8018
2940510 | 지상 3층 | 24 | AW | 지상 3층 | 상위 레벨: 지상 4층 | 4100 | 80 | 80 | 37400 | 153.34
2944600 | 지상 4층 | 24 | AW | 지상 4층 | 상위 레벨: 지상 5층 | 2620 | 80 | -1400 | 37400.6 | 97.9896
2945775 | 지상 3층 | 25 | AW | 지상 3층 | 상위 레벨: 지상 4층 | 2620 | 80 | -1400 | 27991 | 73.3128
2948716 | 지상 4층 | 25 | AW | 지상 4층 | 상위 레벨: 지상 5층 | 4100 | -1400 | -1400 | 11800 | 48.38
2949931 | 지상 4층 | 25 | AW | 지상 4층 | 상위 레벨: 지상 5층 | 2100 | 600 | -1400 | 15382 | 32.3022
2951075 | 지상 3층 | 26 | AW | 지상 3층 | 상위 레벨: 지상 4층 | 2620 | 80 | -1400 | 8991.01 | 23.5564
2960446 | 지상 10층 | 27 | AW | 지상 10층 | 상위 레벨: 옥탑층 | 3000 | 600 | -1400 | 34750 | 104.25
2970485 | 지상 10층 | 28 | AW | 지상 10층 | 상위 레벨: 옥탑층 | 3000 | 600 | -1400 | 37500.7 | 112.502
2971239 | 지상 5층 | 29 | AW | 지상 5층 | 상위 레벨: 지상 6층 | 2000 | 600 | -1500 | 27982 | 55.964
2975042 | 지상 6층 | 29 | AW | 지상 6층 | 상위 레벨: 지상 7층 | 2000 | 600 | -1500 | 27982 | 55.964
2975402 | 지상 7층 | 29 | AW | 지상 7층 | 상위 레벨: 지상 8층 | 2000 | 600 | -1500 | 27800 | 55.6
2975762 | 지상 8층 | 29 | AW | 지상 8층 | 상위 레벨: 지상 9층 | 2000 | 600 | -1500 | 27982 | 55.964
2976122 | 지상 9층 | 29 | AW | 지상 9층 | 상위 레벨: 지상 10층 | 2500 | 600 | -1400 | 27800 | 69.5
2976482 | 지상 10층 | 29 | AW | 지상 10층 | 상위 레벨: 옥탑층 | 3000 | 600 | -1400 | 28000 | 84
3050431 | 지하2층 | 1 | SSD | 지하2층 | 상위 레벨: 지하1층 | 2390 | 200 | -1410 | 2500 | 5.975
3050663 | 지하2층 | 1 | SSD | 지하2층 | 상위 레벨: 지하1층 | 2390 | 200 | -1410 | 5055 | 12.0815
3050962 | 지하2층 | 1 | SSD | 지하2층 | 상위 레벨: 지하1층 | 2390 | 200 | -1410 | 2600 | 6.214
3054003 | 지하1층 | 1 | SSD | 지하1층 | 상위 레벨: GL | 2600 | 200 | -3150 | 2496.09 | 6.48984
3054009 | 지하1층 | 1 | SSD | 지하1층 | 상위 레벨: GL | 2600 | 200 | -3150 | 5050 | 13.13
3054015 | 지하1층 | 1 | SSD | 지하1층 | 상위 레벨: GL | 2600 | 200 | -3150 | 2596.09 | 6.74983
3118405 | 지상 1층 | 7 | SSD | 지상 1층 | 상위 레벨: 지상 2층 | 3520 | 80 | -1200 | 2590.02 | 8.95846
3181685 | 지상 2층 | 13 | SSD | 지상 2층 | 상위 레벨: 지상 3층 | 2020 | 80 | -2400 | 1300.01 | 2.62602
3181710 | 지상 3층 | 13 | SSD | 지상 3층 | 상위 레벨: 지상 4층 | 2020 | 80 | -2000 | 1250 | 2.525
3181731 | 지상 4층 | 13 | SSD | 지상 4층 | 상위 레벨: 지상 5층 | 2020 | 80 | -2000 | 1250 | 0.70275
3181752 | 지상 5층 | 13 | SSD | 지상 5층 | 상위 레벨: 지상 6층 | 2020 | 80 | -2000 | 1300.01 | 0.803768
3181773 | 지상 6층 | 13 | SSD | 지상 6층 | 상위 레벨: 지상 7층 | 2020 | 80 | -2000 | 1300.01 | 0.803768
3181794 | 지상 7층 | 13 | SSD | 지상 7층 | 상위 레벨: 지상 8층 | 2020 | 80 | -2000 | 1300.01 | 0.803768
3181815 | 지상 8층 | 13 | SSD | 지상 8층 | 상위 레벨: 지상 9층 | 2020 | 80 | -2000 | 1300.01 | 0.803768
3181836 | 지상 9층 | 13 | SSD | 지상 9층 | 상위 레벨: 지상 10층 | 2020 | 80 | -2400 | 1300.01 | 0.803768
3181857 | 지상 10층 | 13 | SSD | 지상 10층 | 상위 레벨: 옥탑층 | 2020 | 80 | -2900 | 1510.01 | 1.22797
5355390 | 지상 4층 | 25 | SSD | 지상 4층 | 상위 레벨: 지상 5층 | 2620 | 80 | -1400 | 2600 | 6.55
5355417 | 지상 4층 | 26 | SSD | 지상 4층 | 상위 레벨: 지상 5층 | 2620 | 80 | -1400 | 6600 | 14.1795
5355471 | 지상 4층 | 25 | SSD | 지상 4층 | 상위 레벨: 지상 5층 | 2620 | 80 | -1400 | 2500.03 | 6.55009
5355498 | 지상 4층 | 28 | SSD | 지상 4층 | 상위 레벨: 지상 5층 | 2620 | 80 | -1400 | 9900 | 25.938
5389070 | 지상 4층 | 29 | SSD | 지상 4층 | 상위 레벨: 지상 5층 | 2620 | 80 | -1400 | 2235 | 5.8557
5389520 | 지상 4층 | 29 | SSD | 지상 4층 | 상위 레벨: 지상 5층 | 2620 | 80 | -1400 | 2690.03 | 3.93539
5393177 | 지상 9층 | 29 | SSD | 지상 9층 | 상위 레벨: 지상 10층 | 3020 | 80 | -1400 | 2300 | 6.946
5393183 | 지상 9층 | 29 | SSD | 지상 9층 | 상위 레벨: 지상 10층 | 3020 | 80 | -1400 | 2690 | 5.0113
5393189 | 지상 9층 | 29 | SSD | 지상 9층 | 상위 레벨: 지상 10층 | 3020 | 80 | -1400 | 2795 | 5.3284
5396619 | 지상 5층 | 25 | SSD | 지상 5층 | 상위 레벨: 지상 6층 | 2620 | 80 | -1400 | 2600 | 3.54125
5396648 | 지상 6층 | 25 | SSD | 지상 6층 | 상위 레벨: 지상 7층 | 2620 | 80 | -1400 | 2600.01 | 3.54127
5396677 | 지상 7층 | 25 | SSD | 지상 7층 | 상위 레벨: 지상 8층 | 2620 | 80 | -1400 | 2600 | 3.54125
5396706 | 지상 8층 | 25 | SSD | 지상 8층 | 상위 레벨: 지상 9층 | 2620 | 80 | -1400 | 2600.01 | 3.54127
5397131 | 지상 5층 | 27 | SSD | 지상 5층 | 상위 레벨: 지상 6층 | 2620 | 80 | -1400 | 6500 | 13.9175
5397158 | 지상 5층 | 26 | SSD | 지상 5층 | 상위 레벨: 지상 6층 | 2620 | 80 | -1400 | 6600 | 14.1795
5397187 | 지상 6층 | 27 | SSD | 지상 6층 | 상위 레벨: 지상 7층 | 2620 | 80 | -1400 | 6500 | 13.9175
5397214 | 지상 6층 | 26 | SSD | 지상 6층 | 상위 레벨: 지상 7층 | 2620 | 80 | -1400 | 6600 | 14.1795
5397243 | 지상 7층 | 27 | SSD | 지상 7층 | 상위 레벨: 지상 8층 | 2620 | 80 | -1400 | 6494.97 | 13.9043
5397270 | 지상 7층 | 26 | SSD | 지상 7층 | 상위 레벨: 지상 8층 | 2620 | 80 | -1400 | 6600 | 14.1795
5397299 | 지상 8층 | 27 | SSD | 지상 8층 | 상위 레벨: 지상 9층 | 2620 | 80 | -1400 | 6499.97 | 13.9174
5397326 | 지상 8층 | 26 | SSD | 지상 8층 | 상위 레벨: 지상 9층 | 2620 | 80 | -1400 | 6800.03 | 14.7036
5398141 | 지상 5층 | 25 | SSD | 지상 5층 | 상위 레벨: 지상 6층 | 2620 | 80 | -1400 | 2500.02 | 3.43755
5398170 | 지상 6층 | 25 | SSD | 지상 6층 | 상위 레벨: 지상 7층 | 2620 | 80 | -1400 | 2500 | 3.4375
5398199 | 지상 7층 | 25 | SSD | 지상 7층 | 상위 레벨: 지상 8층 | 2620 | 80 | -1400 | 2543.15 | 3.55054
5398228 | 지상 8층 | 25 | SSD | 지상 8층 | 상위 레벨: 지상 9층 | 2620 | 80 | -1400 | 2500.02 | 3.43755
5398672 | 지상 5층 | 28 | SSD | 지상 5층 | 상위 레벨: 지상 6층 | 2620 | 80 | -1400 | 9900.02 | 22.8255
5398717 | 지상 6층 | 28 | SSD | 지상 6층 | 상위 레벨: 지상 7층 | 2620 | 80 | -1400 | 9899.98 | 22.8254
5398762 | 지상 7층 | 28 | SSD | 지상 7층 | 상위 레벨: 지상 8층 | 2620 | 80 | -1400 | 9900 | 22.8255
5398807 | 지상 8층 | 28 | SSD | 지상 8층 | 상위 레벨: 지상 9층 | 2620 | 80 | -1400 | 10000 | 23.0875
5403428 | 지상 5층 | 29 | SSD | 지상 5층 | 상위 레벨: 지상 6층 | 2620 | 80 | -1400 | 2195 | 5.7509
5403439 | 지상 5층 | 29 | SSD | 지상 5층 | 상위 레벨: 지상 6층 | 2620 | 80 | -1400 | 2700 | 3.93792
5403466 | 지상 6층 | 29 | SSD | 지상 6층 | 상위 레벨: 지상 7층 | 2620 | 80 | -1400 | 2195 | 5.7509
5403477 | 지상 6층 | 29 | SSD | 지상 6층 | 상위 레벨: 지상 7층 | 2620 | 80 | -1400 | 2640 | 3.6864
5403504 | 지상 7층 | 29 | SSD | 지상 7층 | 상위 레벨: 지상 8층 | 2620 | 80 | -1400 | 2199.98 | 5.76396
5403515 | 지상 7층 | 29 | SSD | 지상 7층 | 상위 레벨: 지상 8층 | 2620 | 80 | -1400 | 2645 | 3.6995
5403542 | 지상 8층 | 29 | SSD | 지상 8층 | 상위 레벨: 지상 9층 | 2620 | 80 | -1400 | 2295.02 | 6.01295
5403553 | 지상 8층 | 29 | SSD | 지상 8층 | 상위 레벨: 지상 9층 | 2620 | 80 | -1400 | 2635 | 3.6733
5403580 | 지상 4층 | 29 | SSD | 지상 4층 | 상위 레벨: 지상 5층 | 2620 | 80 | -1400 | 2750.01 | 4.09252
5403601 | 지상 5층 | 29 | SSD | 지상 5층 | 상위 레벨: 지상 6층 | 2620 | 80 | -1400 | 2800 | 4.2235
5403620 | 지상 6층 | 29 | SSD | 지상 6층 | 상위 레벨: 지상 7층 | 2620 | 80 | -1400 | 2795 | 4.2104
5403639 | 지상 7층 | 29 | SSD | 지상 7층 | 상위 레벨: 지상 8층 | 2620 | 80 | -1400 | 2795 | 4.2104
5403658 | 지상 8층 | 29 | SSD | 지상 8층 | 상위 레벨: 지상 9층 | 2620 | 80 | -1400 | 2795 | 4.2104
5403677 | 지상 10층 | 29 | SSD | 지상 10층 | 상위 레벨: 옥탑층 | 3520 | 80 | -1400 | 2300 | 8.096
5403690 | 지상 10층 | 29 | SSD | 지상 10층 | 상위 레벨: 옥탑층 | 3520 | 80 | -1400 | 2649.97 | 6.05698
5403726 | 지상 10층 | 29 | SSD | 지상 10층 | 상위 레벨: 옥탑층 | 3520 | 80 | -1400 | 2800.01 | 6.74353
5405305 | 지상 3층 | 27 | SSD | 지상 3층 | 상위 레벨: 지상 4층 | 2620 | 80 | -1400 | 6500.03 | 17.0301
5405786 | 지상 3층 | 29 | SSD | 지상 3층 | 상위 레벨: 지상 4층 | 2620 | 80 | -1400 | 2250 | 5.895
5405797 | 지상 3층 | 29 | SSD | 지상 3층 | 상위 레벨: 지상 4층 | 2620 | 80 | -1400 | 2750 | 7.205
5818108 | 지상 9층 | 28 | AW | 지상 9층 | 상위 레벨: 지상 10층 | 2500 | 600 | -1400 | 37500 | 93.75
5818681 | 지상 9층 | 27 | AW | 지상 9층 | 상위 레벨: 지상 10층 | 2500 | 600 | -1400 | 34750 | 86.875
5819254 | 지상 8층 | 28 | AW | 지상 8층 | 상위 레벨: 지상 9층 | 2000 | 600 | -1500 | 37500.6 | 75.0012
5819642 | 지상 8층 | 27 | AW | 지상 8층 | 상위 레벨: 지상 9층 | 2000 | 600 | -1500 | 34750.1 | 69.5002
5820121 | 지상 7층 | 28 | AW | 지상 7층 | 상위 레벨: 지상 8층 | 2000 | 600 | -1500 | 37500 | 75
5820509 | 지상 7층 | 27 | AW | 지상 7층 | 상위 레벨: 지상 8층 | 2000 | 600 | -1500 | 34749.8 | 69.4997
5821009 | 지상 6층 | 28 | AW | 지상 6층 | 상위 레벨: 지상 7층 | 2000 | 600 | -1500 | 37500 | 75
5821397 | 지상 6층 | 27 | AW | 지상 6층 | 상위 레벨: 지상 7층 | 2000 | 600 | -1500 | 34750 | 69.5001
5821878 | 지상 5층 | 28 | AW | 지상 5층 | 상위 레벨: 지상 6층 | 2000 | 600 | -1500 | 37500 | 75
5822266 | 지상 5층 | 27 | AW | 지상 5층 | 상위 레벨: 지상 6층 | 2000 | 600 | -1500 | 34750 | 69.5001
5909172 | 지상 2층 | 26 | SSD | 지상 2층 | 상위 레벨: 지상 3층 | 3020 | 80 | -1400 | 2850 | 8.305
5909202 | 지상 9층 | 26 | SSD | 지상 9층 | 상위 레벨: 지상 10층 | 3020 | 80 | -1400 | 2850 | 5.1925
5909232 | 지상 10층 | 26 | SSD | 지상 10층 | 상위 레벨: 옥탑층 | 3520 | 80 | -1400 | 2832.03 | 6.50423
7697250 | 지상 3층 |  | SSD | 지상 3층 | 상위 레벨: 지상 4층 | 2620 | 80 | -1400 | 2850 | 7.467

# IfcDistributionPort (168)
Description: Flow
Name | FlowDirection | Group
InPort_7855330 | SINK | 기계 Supply Air 1
OutPort_7855243 | SOURCE | 기계 Supply Air 1
InPort_7855243 | SINK | 기계 Supply Air 1
OutPort_7855272 | SOURCE | 기계 Supply Air 1
Port_7855244 | SINK | 기계 Supply Air 1
InPort_7855272 | SINK | 기계 Supply Air 1
OutPort_7855244 | SOURCE | 기계 Supply Air 1
4 x InPort_7855245 | SOURCEANDSINK | 기계 Supply Air 2
OutPort_7855293 | SOURCEANDSINK | 기계 Supply Air 2
OutPort_7855290 | SOURCEANDSINK | 기계 Supply Air 2
InPort_7855256 | SINK | 기계 Supply Air 2
OutPort_7855245 | SOURCE | 기계 Supply Air 2
OutPort_7855296 | SOURCEANDSINK | 기계 Supply Air 2
OutPort_7855246 | SOURCEANDSINK | 기계 Supply Air 2
Port_7855246 | SOURCEANDSINK | 기계 Supply Air 2
Port_7855247 | SOURCEANDSINK | 기계 Return Air 1
InPort_7855247 | SOURCEANDSINK | 기계 Return Air 1
OutPort_7855271 | SOURCEANDSINK | 기계 Return Air 1
2 x InPort_7855248 | SOURCEANDSINK | 기계 Return Air 6
OutPort_7855270 | SOURCEANDSINK | 기계 Return Air 6
2 x OutPort_7855278 | SOURCEANDSINK | 기계 Return Air 6
2 x InPort_7855249 | SOURCEANDSINK | 기계 Return Air 6
2 x OutPort_7855286 | SOURCEANDSINK | 기계 Return Air 6
OutPort_7855257 | SOURCEANDSINK | 기계 Return Air 6
4 x InPort_7855250 | SOURCEANDSINK | 기계 Return Air 2
OutPort_7855305 | SOURCEANDSINK | 기계 Return Air 2
OutPort_7855302 | SOURCEANDSINK | 기계 Return Air 2
OutPort_7855299 | SOURCEANDSINK | 기계 Return Air 2
InPort_7855250 | SINK | 기계 Return Air 2
OutPort_7855255 | SOURCE | 기계 Return Air 2
OutPort_7855251 | SOURCEANDSINK | 기계 Return Air 2
Port_7855251 | SOURCEANDSINK | 기계 Return Air 2
InPort_7855252 | SINK | 기계 Return Air 3
OutPort_7855254 | SOURCE | 기계 Return Air 3
3 x InPort_7855252 | SOURCEANDSINK | 기계 Return Air 3
OutPort_7855311 | SOURCEANDSINK | 기계 Return Air 3
OutPort_7855308 | SOURCEANDSINK | 기계 Return Air 3
OutPort_7855253 | SOURCEANDSINK | 기계 Return Air 3
Port_7855253 | SOURCEANDSINK | 기계 Return Air 3
InPort_7855257 | SOURCEANDSINK | 기계 Return Air 7
OutPort_7855262 | SOURCEANDSINK | 기계 Return Air 7
InPort_7855257 | SOURCEANDSINK | 기계 Return Air 8
OutPort_7855258 | SOURCEANDSINK | 기계 Return Air 8
InPort_7855258 | SOURCEANDSINK | 기계 Return Air 8
2 x OutPort_7855269 | SOURCEANDSINK | 기계 Return Air 8
3 x InPort_7855260 | SOURCEANDSINK | 기계 Return Air 8
OutPort_7855326 | SOURCEANDSINK | 기계 Return Air 8
InPort_7855260 | SINK | 기계 Return Air 8
OutPort_7855265 | SOURCE | 기계 Return Air 8
OutPort_7855329 | SOURCEANDSINK | 기계 Return Air 8
InPort_7855262 | SINK | 기계 Return Air 7
OutPort_7855264 | SOURCE | 기계 Return Air 7
2 x InPort_7855262 | SOURCEANDSINK | 기계 Return Air 7
OutPort_7855320 | SOURCEANDSINK | 기계 Return Air 7
OutPort_7855323 | SOURCEANDSINK | 기계 Return Air 7
3 x InPort_7855266 | SOURCEANDSINK | 기계 Supply Air 4
OutPort_7855267 | SOURCEANDSINK | 기계 Supply Air 4
OutPort_7855317 | SOURCEANDSINK | 기계 Supply Air 4
InPort_7855266 | SINK | 기계 Supply Air 4
OutPort_7855268 | SOURCE | 기계 Supply Air 4
OutPort_7855314 | SOURCEANDSINK | 기계 Supply Air 4
Port_7855267 | SOURCEANDSINK | 기계 Supply Air 4
InPort_7855270 | SOURCEANDSINK | 기계 Return Air 6
OutPort_7855280 | SOURCEANDSINK | 기계 Return Air 6
InPort_7855271 | SOURCEANDSINK | 기계 Return Air 1
OutPort_7855273 | SOURCEANDSINK | 기계 Return Air 1
InPort_7855273 | SOURCEANDSINK | 기계 Return Air 1
2 x OutPort_7855275 | SOURCEANDSINK | 기계 Return Air 1
2 x InPort_7855274 | SOURCEANDSINK | 기계 Return Air 1
OutPort_7855277 | SOURCEANDSINK | 기계 Return Air 1
2 x InPort_7855276 | SOURCEANDSINK | 기계 Return Air 6
OutPort_7855279 | SOURCEANDSINK | 기계 Return Air 6
Port_7855277 | SOURCEANDSINK | 기계 Return Air 1
Port_7855279 | SOURCEANDSINK | 기계 Return Air 6
InPort_7855280 | SOURCEANDSINK | 기계 Return Air 6
2 x OutPort_7855283 | SOURCEANDSINK | 기계 Return Air 6
2 x InPort_7855281 | SOURCEANDSINK | 기계 Return Air 6
2 x OutPort_7855285 | SOURCEANDSINK | 기계 Return Air 6
2 x OutPort_7855287 | SOURCEANDSINK | 기계 Return Air 6
2 x InPort_7855282 | SOURCEANDSINK | 기계 Return Air 6
2 x InPort_7855284 | SOURCEANDSINK | 기계 Return Air 6
2 x Port_7855288 | SOURCEANDSINK | 기계 Supply Air 6
Port_7855290 | SOURCEANDSINK | 기계 Supply Air 2
2 x Port_7855291 | SOURCEANDSINK | 기계 Supply Air 8
Port_7855293 | SOURCEANDSINK | 기계 Supply Air 2
2 x Port_7855294 | SOURCEANDSINK | 기계 Supply Air 10
Port_7855296 | SOURCEANDSINK | 기계 Supply Air 2
2 x Port_7855297 | SOURCEANDSINK | 기계 Return Air 14
Port_7855299 | SOURCEANDSINK | 기계 Return Air 2
2 x Port_7855300 | SOURCEANDSINK | 기계 Return Air 16
Port_7855302 | SOURCEANDSINK | 기계 Return Air 2
2 x Port_7855303 | SOURCEANDSINK | 기계 Return Air 18
Port_7855305 | SOURCEANDSINK | 기계 Return Air 2
2 x Port_7855306 | SOURCEANDSINK | 기계 Return Air 20
Port_7855308 | SOURCEANDSINK | 기계 Return Air 3
2 x Port_7855309 | SOURCEANDSINK | 기계 Return Air 22
Port_7855311 | SOURCEANDSINK | 기계 Return Air 3
2 x Port_7855312 | SOURCEANDSINK | 기계 Supply Air 12
Port_7855314 | SOURCEANDSINK | 기계 Supply Air 4
2 x Port_7855315 | SOURCEANDSINK | 기계 Supply Air 14
Port_7855317 | SOURCEANDSINK | 기계 Supply Air 4
2 x Port_7855318 | SOURCEANDSINK | 기계 Return Air 24
Port_7855320 | SOURCEANDSINK | 기계 Return Air 7
2 x Port_7855321 | SOURCEANDSINK | 기계 Return Air 26
Port_7855323 | SOURCEANDSINK | 기계 Return Air 7
2 x Port_7855324 | SOURCEANDSINK | 기계 Return Air 28
Port_7855326 | SOURCEANDSINK | 기계 Return Air 8
2 x Port_7855327 | SOURCEANDSINK | 기계 Return Air 30
Port_7855329 | SOURCEANDSINK | 기계 Return Air 8
2 x InPort_7855331 | SOURCEANDSINK
2 x OutPort_7855333 | SOURCEANDSINK
2 x OutPort_7855335 | SOURCEANDSINK
Port_7855332 | SOURCEANDSINK
InPort_7855332 | SOURCEANDSINK
InPort_7855334 | SOURCEANDSINK
Port_7855334 | SOURCEANDSINK
InPort_7855335 | SOURCEANDSINK
OutPort_7855336 | SOURCEANDSINK
Port_7855336 | SOURCEANDSINK
2 x Port_7855337 | SOURCEANDSINK
InPort_7855337 | SOURCEANDSINK
OutPort_7855338 | SOURCEANDSINK
Port_7855338 | SOURCEANDSINK

# IfcDoor: DR111-외여닫이문(철재, 일반):DR111-외여닫이문(철재, 일반) 1100x2100mm 2 (4)
Type - OperationType: SINGLE_SWING_LEFT; ParameterTakesPrecedence: no; Sizeable: no; Material: <Unnamed> (10), KBIMS-철재, KBIMS-철재 프레임
Type - ID 데이터(Type) - OmniClass 번호: 23.30.10.00; OmniClass 제목: Doors; 유형 마크: 135; 유형 이름: DR111-외여닫이문(철재, 일반) 1100x2100mm 2
Type - 기타(Type) - 카테고리: 문; 성능-도장포함 여부: no; 성능-유리포함 여부: no; KBIMS-부위코드: E333; 건설정보분류체계-부위분류: E333; 성능-방화등급: 갑종; 제작정보: AIBIM-2023; 조달청표준공사코드: ALA110100000; 조달청표준공사코드-세부공종: ALA120103000; 패밀리 이름: DR111-외여닫이문(철재, 일반)
Type - 시공(Type) - 기능: 내부; 벽 마무리: 호스트별
Type - 재료 및 마감재(Type) - 문패널 재료: KBIMS-철재; 문프레임 재료: KBIMS-철재 프레임
Type - 치수(Type) - 두께: 0 mm; 높이: 2100 mm; 문패널 두께: 30 mm; 문프레임 돌출 두께: 30 mm; 문프레임 폭: 60 mm; 문프레임 홈: 30 mm; 패널 폭: 1040 mm; 폭: 1100 mm
Type - 해석 특성(Type) - 열 특성 정의 기준: 개략적 유형; 해석 시공: <없음>
Type - DR111-외여닫이문(철재, 일반):DR111-외여닫이문(철재, 일반) 1100x2100mm 2:3043795:1 - PanelOperation: SWINGING
Type - Pset_DoorCommon - IsExternal: no
OverallHeight: 2100 mm; OverallWidth: 1100 mm
Pset_DoorCommon - Reference: DR111-외여닫이문(철재, 일반) 1100x2100mm 2
Pset_QuantityTakeOff - Reference: DR111-외여닫이문(철재, 일반) 1100x2100mm 2
BaseQuantities - Height: 2100 mm; Width: 1100 mm; Area: 2.31 m2
공정 - 생성 공정: 새 구성
기타 - 카테고리: 문; 유형: DR111-외여닫이문(철재, 일반) 1100x2100mm 2; 유형 ID: 8088344; 패밀리: DR111-외여닫이문(철재, 일반); 패밀리 및 유형: DR111-외여닫이문(철재, 일반): DR111-외여닫이문(철재, 일반) 1100x2100mm 2
치수 - 면적: 3.66584 m2; 벽체 opening 면적: 2.31 m2; 체적: 0.122657 m3
Name (DR111-외여닫이문(철재, 일반):DR111-외여닫이문(철재, 일반) 1100x2100mm 2:...) | In | 레벨 | 씰 높이 (mm) | 헤드 높이 (mm) | 호스트 ID | Material
3043795 | 지하2층 | 지하2층 | 200 | 2300 | 2813523
3094450 | 옥탑층 | 옥탑층 | 80 | 2180 | 2822839 | <Unnamed>, KBIMS-철재, KBIMS-철재 프레임
3158435 | 옥탑층 | 옥탑층 | 80 | 2180 | 2822813 | <Unnamed>, KBIMS-철재, KBIMS-철재 프레임
5862534 | 지상 1층 | 지상 1층 | 80 | 2180 | 2818039 | <Unnamed>, KBIMS-철재, KBIMS-철재 프레임

# IfcDoor: DR111-외여닫이문(철재, 일반):DR111-외여닫이문(철재, 일반) 1100x2100mm 2, DR111-외여닫이문(철재, 일반):DR111-외여닫이문(철재, 일반) 1100x2100mm 2:3046012
In: 지하1층
Type - OperationType: SINGLE_SWING_LEFT; ParameterTakesPrecedence: no; Sizeable: no; Material: <Unnamed> (10), KBIMS-철재, KBIMS-철재 프레임
Type - ID 데이터(Type) - OmniClass 번호: 23.30.10.00; OmniClass 제목: Doors; 유형 마크: 135; 유형 이름: DR111-외여닫이문(철재, 일반) 1100x2100mm 2
Type - 기타(Type) - 카테고리: 문; 성능-도장포함 여부: no; 성능-유리포함 여부: no; KBIMS-부위코드: E333; 건설정보분류체계-부위분류: E333; 성능-방화등급: 갑종; 제작정보: AIBIM-2023; 조달청표준공사코드: ALA110100000; 조달청표준공사코드-세부공종: ALA120103000; 패밀리 이름: DR111-외여닫이문(철재, 일반)
Type - 시공(Type) - 기능: 내부; 벽 마무리: 호스트별
Type - 재료 및 마감재(Type) - 문패널 재료: KBIMS-철재; 문프레임 재료: KBIMS-철재 프레임
Type - 치수(Type) - 두께: 0 mm; 높이: 2100 mm; 문패널 두께: 30 mm; 문프레임 돌출 두께: 30 mm; 문프레임 폭: 60 mm; 문프레임 홈: 30 mm; 패널 폭: 1040 mm; 폭: 1100 mm
Type - 해석 특성(Type) - 열 특성 정의 기준: 개략적 유형; 해석 시공: <없음>
Type - DR111-외여닫이문(철재, 일반):DR111-외여닫이문(철재, 일반) 1100x2100mm 2:3046012:1 - PanelOperation: SWINGING
Type - Pset_DoorCommon - IsExternal: no
OverallHeight: 2100 mm; OverallWidth: 1100 mm
Pset_DoorCommon - Reference: DR111-외여닫이문(철재, 일반) 1100x2100mm 2
Pset_QuantityTakeOff - Reference: DR111-외여닫이문(철재, 일반) 1100x2100mm 2
BaseQuantities - Height: 2100 mm; Width: 1100 mm; Area: 2.31 m2
공정 - 생성 공정: 새 구성
구속조건 - 레벨: 지하1층; 씰 높이: 200 mm
기타 - 카테고리: 문; 유형: DR111-외여닫이문(철재, 일반) 1100x2100mm 2; 유형 ID: 8088344; 패밀리: DR111-외여닫이문(철재, 일반); 패밀리 및 유형: DR111-외여닫이문(철재, 일반): DR111-외여닫이문(철재, 일반) 1100x2100mm 2; 헤드 높이: 2300 mm; 호스트 ID: 2816471
치수 - 면적: 3.66584 m2; 벽체 opening 면적: 2.31 m2; 체적: 0.122657 m3

# IfcDoor: DR111-외여닫이문(철재, 일반):DR111-외여닫이문(철재, 일반) 1100x2100mm 2 (9)
Type - OperationType: SINGLE_SWING_RIGHT; ParameterTakesPrecedence: no; Sizeable: no; Material: <Unnamed> (10), KBIMS-철재, KBIMS-철재 프레임
Type - ID 데이터(Type) - OmniClass 번호: 23.30.10.00; OmniClass 제목: Doors; 유형 마크: 135; 유형 이름: DR111-외여닫이문(철재, 일반) 1100x2100mm 2
Type - 기타(Type) - 카테고리: 문; 성능-도장포함 여부: no; 성능-유리포함 여부: no; KBIMS-부위코드: E333; 건설정보분류체계-부위분류: E333; 성능-방화등급: 갑종; 제작정보: AIBIM-2023; 조달청표준공사코드: ALA110100000; 조달청표준공사코드-세부공종: ALA120103000; 패밀리 이름: DR111-외여닫이문(철재, 일반)
Type - 시공(Type) - 기능: 내부; 벽 마무리: 호스트별
Type - 재료 및 마감재(Type) - 문패널 재료: KBIMS-철재; 문프레임 재료: KBIMS-철재 프레임
Type - 치수(Type) - 두께: 0 mm; 높이: 2100 mm; 문패널 두께: 30 mm; 문프레임 돌출 두께: 30 mm; 문프레임 폭: 60 mm; 문프레임 홈: 30 mm; 패널 폭: 1040 mm; 폭: 1100 mm
Type - 해석 특성(Type) - 열 특성 정의 기준: 개략적 유형; 해석 시공: <없음>
Type - DR111-외여닫이문(철재, 일반):DR111-외여닫이문(철재, 일반) 1100x2100mm 2:3081194:1 - PanelOperation: SWINGING
Type - Pset_DoorCommon - IsExternal: no
OverallHeight: 2100 mm; OverallWidth: 1100 mm
Pset_DoorCommon - Reference: DR111-외여닫이문(철재, 일반) 1100x2100mm 2
Pset_QuantityTakeOff - Reference: DR111-외여닫이문(철재, 일반) 1100x2100mm 2
BaseQuantities - Height: 2100 mm; Width: 1100 mm; Area: 2.31 m2
공정 - 생성 공정: 새 구성
구속조건 - 씰 높이: 80 mm
기타 - 카테고리: 문; 유형: DR111-외여닫이문(철재, 일반) 1100x2100mm 2; 유형 ID: 8088344; 패밀리: DR111-외여닫이문(철재, 일반); 패밀리 및 유형: DR111-외여닫이문(철재, 일반): DR111-외여닫이문(철재, 일반) 1100x2100mm 2; 헤드 높이: 2180 mm
치수 - 면적: 3.66584 m2; 벽체 opening 면적: 2.31 m2; 체적: 0.122657 m3
Name (DR111-외여닫이문(철재, 일반):DR111-외여닫이문(철재, 일반) 1100x2100mm 2:...) | In | 레벨 | 호스트 ID | Material
3081194 | 지상 1층 | 지상 1층 | 2818910
3158107 | 지상 2층 | 지상 2층 | 2820024 | <Unnamed>, KBIMS-철재, KBIMS-철재 프레임
3158112 | 지상 3층 | 지상 3층 | 2820443 | <Unnamed>, KBIMS-철재, KBIMS-철재 프레임
3158117 | 지상 4층 | 지상 4층 | 2820693 | <Unnamed>, KBIMS-철재, KBIMS-철재 프레임
3158122 | 지상 5층 | 지상 5층 | 2821195 | <Unnamed>, KBIMS-철재, KBIMS-철재 프레임
3158127 | 지상 6층 | 지상 6층 | 2821455 | <Unnamed>, KBIMS-철재, KBIMS-철재 프레임
3158132 | 지상 7층 | 지상 7층 | 2821651 | <Unnamed>, KBIMS-철재, KBIMS-철재 프레임
3158137 | 지상 8층 | 지상 8층 | 2821997 | <Unnamed>, KBIMS-철재, KBIMS-철재 프레임
3158142 | 지상 9층 | 지상 9층 | 2822203 | <Unnamed>, KBIMS-철재, KBIMS-철재 프레임

# IfcDoor: DR111-외여닫이문(철재, 일반):DR111-외여닫이문(철재, 일반) 1100x2100mm 2, DR111-외여닫이문(철재, 일반):DR111-외여닫이문(철재, 일반) 1100x2100mm 2:3158147
In: 지상 10층
Type - OperationType: SINGLE_SWING_RIGHT; ParameterTakesPrecedence: no; Sizeable: no; Material: <Unnamed> (10), KBIMS-철재, KBIMS-철재 프레임
Type - ID 데이터(Type) - OmniClass 번호: 23.30.10.00; OmniClass 제목: Doors; 유형 마크: 135; 유형 이름: DR111-외여닫이문(철재, 일반) 1100x2100mm 2
Type - 기타(Type) - 카테고리: 문; 성능-도장포함 여부: no; 성능-유리포함 여부: no; KBIMS-부위코드: E333; 건설정보분류체계-부위분류: E333; 성능-방화등급: 갑종; 제작정보: AIBIM-2023; 조달청표준공사코드: ALA110100000; 조달청표준공사코드-세부공종: ALA120103000; 패밀리 이름: DR111-외여닫이문(철재, 일반)
Type - 시공(Type) - 기능: 내부; 벽 마무리: 호스트별
Type - 재료 및 마감재(Type) - 문패널 재료: KBIMS-철재; 문프레임 재료: KBIMS-철재 프레임
Type - 치수(Type) - 두께: 0 mm; 높이: 2100 mm; 문패널 두께: 30 mm; 문프레임 돌출 두께: 30 mm; 문프레임 폭: 60 mm; 문프레임 홈: 30 mm; 패널 폭: 1040 mm; 폭: 1100 mm
Type - 해석 특성(Type) - 열 특성 정의 기준: 개략적 유형; 해석 시공: <없음>
Type - DR111-외여닫이문(철재, 일반):DR111-외여닫이문(철재, 일반) 1100x2100mm 2:3158147:1 - PanelOperation: SWINGING
Type - Pset_DoorCommon - IsExternal: no
OverallHeight: 2100 mm; OverallWidth: 1100 mm
Pset_DoorCommon - Reference: DR111-외여닫이문(철재, 일반) 1100x2100mm 2
Pset_QuantityTakeOff - Reference: DR111-외여닫이문(철재, 일반) 1100x2100mm 2
BaseQuantities - Height: 2100 mm; Width: 1100 mm; Area: 2.31 m2
공정 - 생성 공정: 새 구성
구속조건 - 레벨: 지상 10층; 씰 높이: 80 mm
기타 - 카테고리: 문; 유형: DR111-외여닫이문(철재, 일반) 1100x2100mm 2; 유형 ID: 8088344; 패밀리: DR111-외여닫이문(철재, 일반); 패밀리 및 유형: DR111-외여닫이문(철재, 일반): DR111-외여닫이문(철재, 일반) 1100x2100mm 2; 호스트 ID: 2822389; 헤드 높이: 2180 mm
치수 - 면적: 3.85448 m2; 벽체 opening 면적: 2.31 m2; 체적: 0.133846 m3

# IfcDoor: DR111-외여닫이문(철재, 일반):DR111-외여닫이문(철재, 일반) 900x2100mm, DR111-외여닫이문(철재, 일반):DR111-외여닫이문(철재, 일반) 900x2100mm:5326951
In: 지하2층
Type - OperationType: SINGLE_SWING_LEFT; ParameterTakesPrecedence: no; Sizeable: no; Material: <Unnamed> (10), KBIMS-철재, KBIMS-철재 프레임
Type - ID 데이터(Type) - OmniClass 번호: 23.30.10.00; OmniClass 제목: Doors; 유형 마크: 74; 유형 이름: DR111-외여닫이문(철재, 일반) 900x2100mm; 유형 해설: SD
Type - 기타(Type) - 카테고리: 문; 성능-도장포함 여부: no; 성능-유리포함 여부: no; KBIMS-부위코드: E333; 건설정보분류체계-부위분류: E333; 제작정보: AIBIM-2023; 조달청표준공사코드: ALA110100000; 조달청표준공사코드-세부공종: ALA120103000; 패밀리 이름: DR111-외여닫이문(철재, 일반)
Type - 시공(Type) - 기능: 내부; 벽 마무리: 호스트별
Type - 재료 및 마감재(Type) - 문패널 재료: KBIMS-철재; 문프레임 재료: KBIMS-철재 프레임
Type - 치수(Type) - 두께: 0 mm; 높이: 2100 mm; 문패널 두께: 30 mm; 문프레임 돌출 두께: 30 mm; 문프레임 폭: 60 mm; 문프레임 홈: 30 mm; 패널 폭: 840 mm; 폭: 900 mm
Type - 해석 특성(Type) - 열 특성 정의 기준: 개략적 유형; 해석 시공: <없음>
Type - DR111-외여닫이문(철재, 일반):DR111-외여닫이문(철재, 일반) 900x2100mm:5326951:1 - PanelOperation: SWINGING
Type - Pset_DoorCommon - IsExternal: no
OverallHeight: 2100 mm; OverallWidth: 900 mm
Pset_DoorCommon - Reference: DR111-외여닫이문(철재, 일반) 900x2100mm
Pset_QuantityTakeOff - Reference: DR111-외여닫이문(철재, 일반) 900x2100mm
BaseQuantities - Height: 2100 mm; Width: 900 mm; Area: 1.89 m2
공정 - 생성 공정: 새 구성
구속조건 - 레벨: PIT; 씰 높이: 160 mm
기타 - 카테고리: 문; 패밀리: DR111-외여닫이문(철재, 일반); 유형: DR111-외여닫이문(철재, 일반) 900x2100mm; 유형 ID: 7447208; 패밀리 및 유형: DR111-외여닫이문(철재, 일반): DR111-외여닫이문(철재, 일반) 900x2100mm; 호스트 ID: 2809250; 헤드 높이: 2260 mm
치수 - 면적: 3.19384 m2; 벽체 opening 면적: 1.89 m2; 체적: 0.108017 m3

# IfcDoor: DR111-외여닫이문(철재, 일반):DR111-외여닫이문(철재, 일반) 900x2100mm (14)
Type - OperationType: SINGLE_SWING_RIGHT; ParameterTakesPrecedence: no; Sizeable: no; Material: <Unnamed> (10), KBIMS-철재, KBIMS-철재 프레임
Type - ID 데이터(Type) - OmniClass 번호: 23.30.10.00; OmniClass 제목: Doors; 유형 마크: 74; 유형 이름: DR111-외여닫이문(철재, 일반) 900x2100mm; 유형 해설: SD
Type - 기타(Type) - 카테고리: 문; 성능-도장포함 여부: no; 성능-유리포함 여부: no; KBIMS-부위코드: E333; 건설정보분류체계-부위분류: E333; 제작정보: AIBIM-2023; 조달청표준공사코드: ALA110100000; 조달청표준공사코드-세부공종: ALA120103000; 패밀리 이름: DR111-외여닫이문(철재, 일반)
Type - 시공(Type) - 기능: 내부; 벽 마무리: 호스트별
Type - 재료 및 마감재(Type) - 문패널 재료: KBIMS-철재; 문프레임 재료: KBIMS-철재 프레임
Type - 치수(Type) - 두께: 0 mm; 높이: 2100 mm; 문패널 두께: 30 mm; 문프레임 돌출 두께: 30 mm; 문프레임 폭: 60 mm; 문프레임 홈: 30 mm; 패널 폭: 840 mm; 폭: 900 mm
Type - 해석 특성(Type) - 열 특성 정의 기준: 개략적 유형; 해석 시공: <없음>
Type - DR111-외여닫이문(철재, 일반):DR111-외여닫이문(철재, 일반) 900x2100mm:3081612:1 - PanelOperation: SWINGING
Type - Pset_DoorCommon - IsExternal: no
OverallHeight: 2100 mm; OverallWidth: 900 mm
Pset_DoorCommon - Reference: DR111-외여닫이문(철재, 일반) 900x2100mm
Pset_QuantityTakeOff - Reference: DR111-외여닫이문(철재, 일반) 900x2100mm
BaseQuantities - Height: 2100 mm; Width: 900 mm; Area: 1.89 m2
공정 - 생성 공정: 새 구성
기타 - 카테고리: 문; 패밀리: DR111-외여닫이문(철재, 일반); 유형: DR111-외여닫이문(철재, 일반) 900x2100mm; 유형 ID: 7447208; 패밀리 및 유형: DR111-외여닫이문(철재, 일반): DR111-외여닫이문(철재, 일반) 900x2100mm
치수 - 면적: 3.19384 m2; 벽체 opening 면적: 1.89 m2; 체적: 0.108017 m3
Name (DR111-외여닫이문(철재, 일반):DR111-외여닫이문(철재, 일반) 900x2100mm:...) | In | 레벨 | 씰 높이 (mm) | 헤드 높이 (mm) | 호스트 ID | Material
3081612 | 지상 2층 | 지상 2층 | 80 | 2180 | 2820024
3081618 | 지상 3층 | 지상 3층 | 80 | 2180 | 2820443 | <Unnamed>, KBIMS-철재, KBIMS-철재 프레임
3081624 | 지상 4층 | 지상 4층 | 80 | 2180 | 2820693 | <Unnamed>, KBIMS-철재, KBIMS-철재 프레임
3081630 | 지상 5층 | 지상 5층 | 80 | 2180 | 2821195 | <Unnamed>, KBIMS-철재, KBIMS-철재 프레임
3081636 | 지상 6층 | 지상 6층 | 80 | 2180 | 2821455 | <Unnamed>, KBIMS-철재, KBIMS-철재 프레임
3081642 | 지상 7층 | 지상 7층 | 80 | 2180 | 2821651 | <Unnamed>, KBIMS-철재, KBIMS-철재 프레임
3081648 | 지상 8층 | 지상 8층 | 80 | 2180 | 2821997 | <Unnamed>, KBIMS-철재, KBIMS-철재 프레임
3081654 | 지상 9층 | 지상 9층 | 80 | 2180 | 2822203 | <Unnamed>, KBIMS-철재, KBIMS-철재 프레임
3158476 | 옥탑층 | 옥탑층 | 80 | 2180 | 2822813 | <Unnamed>, KBIMS-철재, KBIMS-철재 프레임
3173908 | 지하2층 | PIT | 160 | 2260 | 2809250 | <Unnamed>, KBIMS-철재, KBIMS-철재 프레임
3174688 | 지하1층 | 지하1층 | 200 | 2300 | 2816467 | <Unnamed>, KBIMS-철재, KBIMS-철재 프레임
5863220 | 지상 1층 | 지상 1층 | 80 | 2180 | 2818039 | <Unnamed>, KBIMS-철재, KBIMS-철재 프레임
5903200 | 지상 3층 | 지상 3층 | 80 | 2180 | 5256435 | <Unnamed>, KBIMS-철재, KBIMS-철재 프레임
5903320 | 지상 9층 | 지상 9층 | 80 | 2180 | 5903103 | <Unnamed>, KBIMS-철재, KBIMS-철재 프레임

# IfcDoor: DR111-외여닫이문(철재, 일반):DR111-외여닫이문(철재, 일반) 900x2100mm (2)
In: 지상 10층
Type - OperationType: SINGLE_SWING_RIGHT; ParameterTakesPrecedence: no; Sizeable: no; Material: <Unnamed> (10), KBIMS-철재, KBIMS-철재 프레임
Type - ID 데이터(Type) - OmniClass 번호: 23.30.10.00; OmniClass 제목: Doors; 유형 마크: 74; 유형 이름: DR111-외여닫이문(철재, 일반) 900x2100mm; 유형 해설: SD
Type - 기타(Type) - 카테고리: 문; 성능-도장포함 여부: no; 성능-유리포함 여부: no; KBIMS-부위코드: E333; 건설정보분류체계-부위분류: E333; 제작정보: AIBIM-2023; 조달청표준공사코드: ALA110100000; 조달청표준공사코드-세부공종: ALA120103000; 패밀리 이름: DR111-외여닫이문(철재, 일반)
Type - 시공(Type) - 기능: 내부; 벽 마무리: 호스트별
Type - 재료 및 마감재(Type) - 문패널 재료: KBIMS-철재; 문프레임 재료: KBIMS-철재 프레임
Type - 치수(Type) - 두께: 0 mm; 높이: 2100 mm; 문패널 두께: 30 mm; 문프레임 돌출 두께: 30 mm; 문프레임 폭: 60 mm; 문프레임 홈: 30 mm; 패널 폭: 840 mm; 폭: 900 mm
Type - 해석 특성(Type) - 열 특성 정의 기준: 개략적 유형; 해석 시공: <없음>
Type - DR111-외여닫이문(철재, 일반):DR111-외여닫이문(철재, 일반) 900x2100mm:3081660:1 - PanelOperation: SWINGING
Type - Pset_DoorCommon - IsExternal: no
OverallHeight: 2100 mm; OverallWidth: 900 mm
Pset_DoorCommon - Reference: DR111-외여닫이문(철재, 일반) 900x2100mm
Pset_QuantityTakeOff - Reference: DR111-외여닫이문(철재, 일반) 900x2100mm
BaseQuantities - Height: 2100 mm; Width: 900 mm; Area: 1.89 m2
공정 - 생성 공정: 새 구성
구속조건 - 레벨: 지상 10층; 씰 높이: 80 mm
기타 - 카테고리: 문; 패밀리: DR111-외여닫이문(철재, 일반); 유형: DR111-외여닫이문(철재, 일반) 900x2100mm; 유형 ID: 7447208; 패밀리 및 유형: DR111-외여닫이문(철재, 일반): DR111-외여닫이문(철재, 일반) 900x2100mm; 헤드 높이: 2180 mm
치수 - 면적: 3.37528 m2; 벽체 opening 면적: 1.89 m2; 체적: 0.118774 m3
Name (DR111-외여닫이문(철재, 일반):DR111-외여닫이문(철재, 일반) 900x2100mm:...) | 호스트 ID
3081660 | 2822389
5903324 | 5903107 | Material: <Unnamed>, KBIMS-철재, KBIMS-철재 프레임

# IfcDoor: DR111-외여닫이문(철재, 일반, 양개):DR111-외여닫이문(유리, 일반, 양개) 1100x1970mm, DR111-외여닫이문(철재, 일반, 양개):DR111-외여닫이문(유리, 일반, 양개) 1100x1970mm:7689199
In: 지상 1층
Type - OperationType: DOUBLE_SWING_LEFT; ParameterTakesPrecedence: no; Sizeable: no; Material: <Unnamed> (2), KBIMS-유리 (2)
Type - DR111-외여닫이문(철재, 일반, 양개):DR111-외여닫이문(유리, 일반, 양개) 1100x1970mm:7689199:1 - PanelOperation: DOUBLE_ACTING
Type - ID 데이터 - OmniClass 번호: 23.30.10.00; OmniClass 제목: Doors; 유형 마크: 112; 유형 이름: DR111-외여닫이문(유리, 일반, 양개) 1100x1970mm; 유형 해설: SD
Type - 기타 - 카테고리: 문; 성능-도장포함 여부: no; 성능-유리포함 여부: no; KBIMS_보급정보-보급코드: bSK-191231; KBIMS_보급정보-저작자: (사)빌딩스마트협회; KBIMS_식별-버전: 1.03; KBIMS-부위코드: E333; 건설정보분류체계-부위분류: E333; 조달청표준공사코드: ALA110100000; 조달청표준공사코드-세부공종: ALA120113000A; 패밀리 이름: DR111-외여닫이문(철재, 일반, 양개)
Type - 시공 - 기능: 내부; 벽 마무리: 호스트별
Type - 재료 및 마감재 - 문패널 재료: KBIMS-유리; 문프레임 재료: KBIMS-유리
Type - 치수 - 두께: 0 mm; 내부 문프레임 돌출 두께: 15 mm; 높이: 1970 mm; 문패널 두께: 15 mm; 문프레임 폭: 30 mm; 외부 문프레임 돌출 두께: 15 mm; 패널 폭: 1040 mm; 폭: 1100 mm
Type - 해석 특성 - 열 특성 정의 기준: 개략적 유형; 해석 시공: <없음>
Type - Pset_DoorCommon - IsExternal: no
OverallHeight: 1970 mm; OverallWidth: 1100 mm
Pset_DoorCommon - Reference: DR111-외여닫이문(유리, 일반, 양개) 1100x1970mm
Pset_QuantityTakeOff - Reference: DR111-외여닫이문(유리, 일반, 양개) 1100x1970mm
BaseQuantities - Height: 1970 mm; Width: 1100 mm; Area: 2.167 m2
ID 데이터 - 마크: 25EEE
공정 - 생성 공정: 새 구성
구속조건 - 레벨: 지상 1층; 씰 높이: -470 mm
기타 - 패밀리: DR111-외여닫이문(철재, 일반, 양개); 유형: DR111-외여닫이문(유리, 일반, 양개) 1100x1970mm; 유형 ID: 7689464; 패밀리 및 유형: DR111-외여닫이문(철재, 일반, 양개): DR111-외여닫이문(유리, 일반, 양개) 1100x1970mm; 헤드 높이: 1500 mm; 호스트 ID: 7689195
치수 - 면적: 2.77525 m2; 벽체 opening 면적: 2.167 m2; 체적: 0.0460077 m3

# IfcDoor: DR111-외여닫이문(철재, 일반, 양개):DR111-외여닫이문(유리, 일반, 양개) 925x1970mm 2 (2)
Type - OperationType: DOUBLE_SWING_LEFT; ParameterTakesPrecedence: no; Sizeable: no; Material: <Unnamed> (2), KBIMS-유리 (2)
Type - ID 데이터(Type) - OmniClass 번호: 23.30.10.00; OmniClass 제목: Doors; 유형 마크: 133; 유형 이름: DR111-외여닫이문(유리, 일반, 양개) 925x1970mm 2; 유형 해설: SD
Type - 기타(Type) - 카테고리: 문; 성능-도장포함 여부: no; 성능-유리포함 여부: no; KBIMS_보급정보-보급코드: bSK-191231; KBIMS_보급정보-저작자: (사)빌딩스마트협회; KBIMS_식별-버전: 1.03; KBIMS-부위코드: E333; 건설정보분류체계-부위분류: E333; 조달청표준공사코드: ALA110100000; 조달청표준공사코드-세부공종: ALA120113000A; 패밀리 이름: DR111-외여닫이문(철재, 일반, 양개)
Type - 시공(Type) - 기능: 내부; 벽 마무리: 호스트별
Type - 재료 및 마감재(Type) - 문패널 재료: KBIMS-유리; 문프레임 재료: KBIMS-유리
Type - 치수(Type) - 두께: 0 mm; 내부 문프레임 돌출 두께: 15 mm; 높이: 1970 mm; 문패널 두께: 15 mm; 문프레임 폭: 30 mm; 외부 문프레임 돌출 두께: 15 mm; 패널 폭: 865 mm; 폭: 925 mm
Type - 해석 특성(Type) - 열 특성 정의 기준: 개략적 유형; 해석 시공: <없음>
Type - DR111-외여닫이문(철재, 일반, 양개):DR111-외여닫이문(유리, 일반, 양개) 925x1970mm 2:7694800:1 - PanelOperation: DOUBLE_ACTING
Type - Pset_DoorCommon - IsExternal: no
OverallHeight: 1970 mm; OverallWidth: 977.5 mm
Pset_DoorCommon - Reference: DR111-외여닫이문(유리, 일반, 양개) 925x1970mm 2
Pset_QuantityTakeOff - Reference: DR111-외여닫이문(유리, 일반, 양개) 925x1970mm 2
BaseQuantities - Height: 1970 mm; Width: 925 mm; Area: 1.82225 m2
공정 - 생성 공정: 새 구성
구속조건 - 씰 높이: 80 mm
기타 - 카테고리: 문; 유형: DR111-외여닫이문(유리, 일반, 양개) 925x1970mm 2; 유형 ID: 7694949; 패밀리: DR111-외여닫이문(철재, 일반, 양개); 패밀리 및 유형: DR111-외여닫이문(철재, 일반, 양개): DR111-외여닫이문(유리, 일반, 양개) 925x1970mm 2; 헤드 높이: 2050 mm
치수 - 면적: 2.41037 m2; 벽체 opening 면적: 1.82225 m2; 체적: 0.0403902 m3
Name (DR111-외여닫이문(철재, 일반, 양개):DR111-외여닫이문(유리, 일반, 양개) 925x1970mm 2:...) | In | 마크 | 레벨 | 호스트 ID
7694800 | 지상 2층 | 25VVV | 지상 2층 | 7690949
7695389 | 지상 3층 | 25WWW | 지상 3층 | 7695377 | Material: <Unnamed>, KBIMS-유리

# IfcDoor: DR111-외여닫이문(철재, 일반, 양개):DR111-외여닫이문(유리, 일반, 양개) 925x1970mm 2 (6)
Type - OperationType: DOUBLE_SWING_LEFT; ParameterTakesPrecedence: no; Sizeable: no; Material: <Unnamed> (2), KBIMS-유리 (2)
Type - ID 데이터(Type) - OmniClass 번호: 23.30.10.00; OmniClass 제목: Doors; 유형 마크: 133; 유형 이름: DR111-외여닫이문(유리, 일반, 양개) 925x1970mm 2; 유형 해설: SD
Type - 기타(Type) - 카테고리: 문; 성능-도장포함 여부: no; 성능-유리포함 여부: no; KBIMS_보급정보-보급코드: bSK-191231; KBIMS_보급정보-저작자: (사)빌딩스마트협회; KBIMS_식별-버전: 1.03; KBIMS-부위코드: E333; 건설정보분류체계-부위분류: E333; 조달청표준공사코드: ALA110100000; 조달청표준공사코드-세부공종: ALA120113000A; 패밀리 이름: DR111-외여닫이문(철재, 일반, 양개)
Type - 시공(Type) - 기능: 내부; 벽 마무리: 호스트별
Type - 재료 및 마감재(Type) - 문패널 재료: KBIMS-유리; 문프레임 재료: KBIMS-유리
Type - 치수(Type) - 두께: 0 mm; 내부 문프레임 돌출 두께: 15 mm; 높이: 1970 mm; 문패널 두께: 15 mm; 문프레임 폭: 30 mm; 외부 문프레임 돌출 두께: 15 mm; 패널 폭: 865 mm; 폭: 925 mm
Type - 해석 특성(Type) - 열 특성 정의 기준: 개략적 유형; 해석 시공: <없음>
Type - DR111-외여닫이문(철재, 일반, 양개):DR111-외여닫이문(유리, 일반, 양개) 925x1970mm 2:7695852:1 - PanelOperation: DOUBLE_ACTING
Type - Pset_DoorCommon - IsExternal: no
OverallHeight: 1970 mm; OverallWidth: 925 mm
Pset_DoorCommon - Reference: DR111-외여닫이문(유리, 일반, 양개) 925x1970mm 2
Pset_QuantityTakeOff - Reference: DR111-외여닫이문(유리, 일반, 양개) 925x1970mm 2
BaseQuantities - Height: 1970 mm; Width: 925 mm; Area: 1.82225 m2
공정 - 생성 공정: 새 구성
구속조건 - 씰 높이: 80 mm
기타 - 카테고리: 문; 유형: DR111-외여닫이문(유리, 일반, 양개) 925x1970mm 2; 유형 ID: 7694949; 패밀리: DR111-외여닫이문(철재, 일반, 양개); 패밀리 및 유형: DR111-외여닫이문(철재, 일반, 양개): DR111-외여닫이문(유리, 일반, 양개) 925x1970mm 2; 헤드 높이: 2050 mm
치수 - 면적: 2.89387 m2; 벽체 opening 면적: 1.82225 m2; 체적: 0.0548052 m3
Name (DR111-외여닫이문(철재, 일반, 양개):DR111-외여닫이문(유리, 일반, 양개) 925x1970mm 2:...) | In | 마크 | 레벨 | 호스트 ID | Material
7695852 | 지상 4층 | 25XXX | 지상 4층 | 2820729
7695861 | 지상 5층 | 25YYY | 지상 5층 | 2821231 | <Unnamed>, KBIMS-유리
7695865 | 지상 6층 | 25ZZZ | 지상 6층 | 2821491 | <Unnamed>, KBIMS-유리
7695868 | 지상 7층 | 25AAAA | 지상 7층 | 2821687 | <Unnamed>, KBIMS-유리
7695871 | 지상 8층 | 25BBBB | 지상 8층 | 2822033 | <Unnamed>, KBIMS-유리
7695874 | 지상 9층 | 25CCCC | 지상 9층 | 2822239 | <Unnamed>, KBIMS-유리

# IfcDoor: DR111-외여닫이문(철재, 일반, 양개):DR111-외여닫이문(유리, 일반, 양개) 925x1970mm 2, DR111-외여닫이문(철재, 일반, 양개):DR111-외여닫이문(유리, 일반, 양개) 925x1970mm 2:7695877
In: 지상 10층
Type - OperationType: DOUBLE_SWING_LEFT; ParameterTakesPrecedence: no; Sizeable: no; Material: <Unnamed> (2), KBIMS-유리 (2)
Type - ID 데이터(Type) - OmniClass 번호: 23.30.10.00; OmniClass 제목: Doors; 유형 마크: 133; 유형 이름: DR111-외여닫이문(유리, 일반, 양개) 925x1970mm 2; 유형 해설: SD
Type - 기타(Type) - 카테고리: 문; 성능-도장포함 여부: no; 성능-유리포함 여부: no; KBIMS_보급정보-보급코드: bSK-191231; KBIMS_보급정보-저작자: (사)빌딩스마트협회; KBIMS_식별-버전: 1.03; KBIMS-부위코드: E333; 건설정보분류체계-부위분류: E333; 조달청표준공사코드: ALA110100000; 조달청표준공사코드-세부공종: ALA120113000A; 패밀리 이름: DR111-외여닫이문(철재, 일반, 양개)
Type - 시공(Type) - 기능: 내부; 벽 마무리: 호스트별
Type - 재료 및 마감재(Type) - 문패널 재료: KBIMS-유리; 문프레임 재료: KBIMS-유리
Type - 치수(Type) - 두께: 0 mm; 내부 문프레임 돌출 두께: 15 mm; 높이: 1970 mm; 문패널 두께: 15 mm; 문프레임 폭: 30 mm; 외부 문프레임 돌출 두께: 15 mm; 패널 폭: 865 mm; 폭: 925 mm
Type - 해석 특성(Type) - 열 특성 정의 기준: 개략적 유형; 해석 시공: <없음>
Type - DR111-외여닫이문(철재, 일반, 양개):DR111-외여닫이문(유리, 일반, 양개) 925x1970mm 2:7695877:1 - PanelOperation: DOUBLE_ACTING
Type - Pset_DoorCommon - IsExternal: no
OverallHeight: 1970 mm; OverallWidth: 925 mm
Pset_DoorCommon - Reference: DR111-외여닫이문(유리, 일반, 양개) 925x1970mm 2
Pset_QuantityTakeOff - Reference: DR111-외여닫이문(유리, 일반, 양개) 925x1970mm 2
BaseQuantities - Height: 1970 mm; Width: 925 mm; Area: 1.82225 m2
ID 데이터 - 마크: 25DDDD
공정 - 생성 공정: 새 구성
구속조건 - 레벨: 지상 10층; 씰 높이: 80 mm
기타 - 카테고리: 문; 유형: DR111-외여닫이문(유리, 일반, 양개) 925x1970mm 2; 유형 ID: 7694949; 패밀리: DR111-외여닫이문(철재, 일반, 양개); 패밀리 및 유형: DR111-외여닫이문(철재, 일반, 양개): DR111-외여닫이문(유리, 일반, 양개) 925x1970mm 2; 헤드 높이: 2050 mm; 호스트 ID: 2822425
치수 - 면적: 3.3677 m2; 벽체 opening 면적: 1.82225 m2; 체적: 0.0689319 m3

# IfcDoor: DR111-외여닫이문(철재, 일반, 양개):DR111-외여닫이문(유리, 일반, 양개) 950x2100mm, DR111-외여닫이문(철재, 일반, 양개):DR111-외여닫이문(유리, 일반, 양개) 950x2100mm:5903316
In: 지상 2층
Type - OperationType: DOUBLE_SWING_LEFT; ParameterTakesPrecedence: no; Sizeable: no; Material: <Unnamed> (2), KBIMS-유리 (2)
Type - DR111-외여닫이문(철재, 일반, 양개):DR111-외여닫이문(유리, 일반, 양개) 950x2100mm:5903316:1 - PanelOperation: DOUBLE_ACTING
Type - ID 데이터 - OmniClass 번호: 23.30.10.00; OmniClass 제목: Doors; 유형 마크: 97; 유형 이름: DR111-외여닫이문(유리, 일반, 양개) 950x2100mm; 유형 해설: SD
Type - 기타 - 카테고리: 문; 성능-도장포함 여부: no; 성능-유리포함 여부: no; KBIMS_보급정보-보급코드: bSK-191231; KBIMS_보급정보-저작자: (사)빌딩스마트협회; KBIMS_식별-버전: 1.03; KBIMS-부위코드: E333; 건설정보분류체계-부위분류: E333; 조달청표준공사코드: ALA110100000; 조달청표준공사코드-세부공종: ALA120113000A; 패밀리 이름: DR111-외여닫이문(철재, 일반, 양개)
Type - 시공 - 기능: 내부; 벽 마무리: 호스트별
Type - 재료 및 마감재 - 문패널 재료: KBIMS-유리; 문프레임 재료: KBIMS-유리
Type - 치수 - 두께: 0 mm; 내부 문프레임 돌출 두께: 15 mm; 높이: 2100 mm; 문패널 두께: 15 mm; 문프레임 폭: 30 mm; 외부 문프레임 돌출 두께: 15 mm; 패널 폭: 890 mm; 폭: 950 mm
Type - 해석 특성 - 열 특성 정의 기준: 개략적 유형; 해석 시공: <없음>
Type - Pset_DoorCommon - IsExternal: no
OverallHeight: 2100 mm; OverallWidth: 950 mm
Pset_DoorCommon - Reference: DR111-외여닫이문(유리, 일반, 양개) 950x2100mm
Pset_QuantityTakeOff - Reference: DR111-외여닫이문(유리, 일반, 양개) 950x2100mm
BaseQuantities - Height: 2100 mm; Width: 950 mm; Area: 1.995 m2
공정 - 생성 공정: 새 구성
구속조건 - 레벨: 지상 2층; 씰 높이: 80 mm
기타 - 패밀리: DR111-외여닫이문(철재, 일반, 양개); 유형: DR111-외여닫이문(유리, 일반, 양개) 950x2100mm; 유형 ID: 7685797; 패밀리 및 유형: DR111-외여닫이문(철재, 일반, 양개): DR111-외여닫이문(유리, 일반, 양개) 950x2100mm; 헤드 높이: 2180 mm; 호스트 ID: 5903096
치수 - 면적: 3.12595 m2; 벽체 opening 면적: 1.995 m2; 체적: 0.0589782 m3

# IfcDoor: DR111-외여닫이문(철재, 일반, 양개):DR111-외여닫이문(유리, 일반, 양개) 950x2100mm (21)
Type - OperationType: DOUBLE_SWING_LEFT; ParameterTakesPrecedence: no; Sizeable: no; Material: <Unnamed> (2), KBIMS-유리 (2)
Type - ID 데이터 - OmniClass 번호: 23.30.10.00; OmniClass 제목: Doors; 유형 마크: 97; 유형 이름: DR111-외여닫이문(유리, 일반, 양개) 950x2100mm; 유형 해설: SD
Type - 기타 - 카테고리: 문; 성능-도장포함 여부: no; 성능-유리포함 여부: no; KBIMS_보급정보-보급코드: bSK-191231; KBIMS_보급정보-저작자: (사)빌딩스마트협회; KBIMS_식별-버전: 1.03; KBIMS-부위코드: E333; 건설정보분류체계-부위분류: E333; 조달청표준공사코드: ALA110100000; 조달청표준공사코드-세부공종: ALA120113000A; 패밀리 이름: DR111-외여닫이문(철재, 일반, 양개)
Type - 시공 - 기능: 내부; 벽 마무리: 호스트별
Type - 재료 및 마감재 - 문패널 재료: KBIMS-유리; 문프레임 재료: KBIMS-유리
Type - 치수 - 두께: 0 mm; 내부 문프레임 돌출 두께: 15 mm; 높이: 2100 mm; 문패널 두께: 15 mm; 문프레임 폭: 30 mm; 외부 문프레임 돌출 두께: 15 mm; 패널 폭: 890 mm; 폭: 950 mm
Type - 해석 특성 - 열 특성 정의 기준: 개략적 유형; 해석 시공: <없음>
Type - DR111-외여닫이문(철재, 일반, 양개):DR111-외여닫이문(유리, 일반, 양개) 950x2100mm:7685884:1 - PanelOperation: DOUBLE_ACTING
Type - Pset_DoorCommon - IsExternal: no
OverallHeight: 2100 mm
Pset_DoorCommon - Reference: DR111-외여닫이문(유리, 일반, 양개) 950x2100mm
Pset_QuantityTakeOff - Reference: DR111-외여닫이문(유리, 일반, 양개) 950x2100mm
BaseQuantities - Height: 2100 mm; Width: 950 mm; Area: 1.995 m2
공정 - 생성 공정: 새 구성
기타 - 패밀리: DR111-외여닫이문(철재, 일반, 양개); 유형: DR111-외여닫이문(유리, 일반, 양개) 950x2100mm; 유형 ID: 7685797; 패밀리 및 유형: DR111-외여닫이문(철재, 일반, 양개): DR111-외여닫이문(유리, 일반, 양개) 950x2100mm
치수 - 면적: 2.61395 m2; 벽체 opening 면적: 1.995 m2; 체적: 0.0437082 m3
Name (DR111-외여닫이문(철재, 일반, 양개):DR111-외여닫이문(유리, 일반, 양개) 950x2100mm:...) | In | OverallWidth (mm) | 마크 | 레벨 | 씰 높이 (mm) | 헤드 높이 (mm) | 호스트 ID | Material
7685884 | 지상 1층 | 950 | 25MM | 지상 1층 | 55 | 2155 | 7681031
7686033 | 지상 1층 | 950 | 25NN | 지상 1층 | 55 | 2155 | 7686028 | <Unnamed>, KBIMS-유리
7686366 | 지상 1층 | 990 | 25OO | 지상 1층 | 55 | 2155 | 7686355 | <Unnamed>, KBIMS-유리
7686436 | 지상 1층 | 990 | 25PP | 지상 1층 | 55 | 2155 | 7686356 | <Unnamed>, KBIMS-유리
7686514 | 지상 1층 | 950 | 25QQ | 지상 1층 | 55 | 2155 | 7686357 | <Unnamed>, KBIMS-유리
7686843 | 지하1층 | 950 | 25SS | GL | -1270 | 830 | 7686359 | <Unnamed>, KBIMS-유리
7686919 | 지하1층 | 990 | 25TT | GL | -1270 | 830 | 7686360 | <Unnamed>, KBIMS-유리
7688084 | 지상 1층 | 990 | 25XX | 지상 1층 | 55 | 2155 | 7688078 | <Unnamed>, KBIMS-유리
7688146 | 지상 1층 | 950 | 25YY | 지상 1층 | 55 | 2155 | 7688077 | <Unnamed>, KBIMS-유리
7688226 | 지상 1층 | 950 | 25ZZ | 지상 1층 | 55 | 2155 | 7688076 | <Unnamed>, KBIMS-유리
7688318 | 지상 1층 | 950 | 25AAA | 지상 1층 | 55 | 2155 | 7688075 | <Unnamed>, KBIMS-유리
7688368 | 지상 1층 | 950 | 25BBB | 지상 1층 | 60 | 2160 | 7688074 | <Unnamed>, KBIMS-유리
7688438 | 지상 1층 | 990 | 25CCC | 지상 1층 | 55 | 2155 | 7688073 | <Unnamed>, KBIMS-유리
7688520 | 지상 1층 | 990 | 25DDD | 지상 1층 | 55 | 2155 | 7688072 | <Unnamed>, KBIMS-유리
7689666 | 지상 1층 | 990 | 25FFF | 지상 1층 | 55 | 2155 | 7689662 | <Unnamed>, KBIMS-유리
7689718 | 지상 1층 | 990 | 25GGG | 지상 1층 | 55 | 2155 | 7689661 | <Unnamed>, KBIMS-유리
7689790 | 지상 1층 | 950 | 25HHH | 지상 1층 | 55 | 2155 | 7689660 | <Unnamed>, KBIMS-유리
7689852 | 지상 1층 | 990 | 25III | 지상 1층 | 55 | 2155 | 7689659 | <Unnamed>, KBIMS-유리
7690070 | 지상 1층 | 990 | 25KKK | 지상 1층 | 55 | 2155 | 7689656 | <Unnamed>, KBIMS-유리
7690144 | 지상 1층 | 990 | 25LLL | 지상 1층 | 55 | 2155 | 7689657 | <Unnamed>, KBIMS-유리
7690246 | 지상 1층 | 990 | 25MMM | 지상 1층 | 55 | 2155 | 7689658 | <Unnamed>, KBIMS-유리

# IfcDoor: DR111-외여닫이문(철재, 일반, 양개):DR111-외여닫이문(유리, 일반, 양개) 950x2100mm (2)
In: 지상 1층
Type - OperationType: DOUBLE_SWING_RIGHT; ParameterTakesPrecedence: no; Sizeable: no; Material: <Unnamed> (2), KBIMS-유리 (2)
Type - ID 데이터 - OmniClass 번호: 23.30.10.00; OmniClass 제목: Doors; 유형 마크: 97; 유형 이름: DR111-외여닫이문(유리, 일반, 양개) 950x2100mm; 유형 해설: SD
Type - 기타 - 카테고리: 문; 성능-도장포함 여부: no; 성능-유리포함 여부: no; KBIMS_보급정보-보급코드: bSK-191231; KBIMS_보급정보-저작자: (사)빌딩스마트협회; KBIMS_식별-버전: 1.03; KBIMS-부위코드: E333; 건설정보분류체계-부위분류: E333; 조달청표준공사코드: ALA110100000; 조달청표준공사코드-세부공종: ALA120113000A; 패밀리 이름: DR111-외여닫이문(철재, 일반, 양개)
Type - 시공 - 기능: 내부; 벽 마무리: 호스트별
Type - 재료 및 마감재 - 문패널 재료: KBIMS-유리; 문프레임 재료: KBIMS-유리
Type - 치수 - 두께: 0 mm; 내부 문프레임 돌출 두께: 15 mm; 높이: 2100 mm; 문패널 두께: 15 mm; 문프레임 폭: 30 mm; 외부 문프레임 돌출 두께: 15 mm; 패널 폭: 890 mm; 폭: 950 mm
Type - 해석 특성 - 열 특성 정의 기준: 개략적 유형; 해석 시공: <없음>
Type - DR111-외여닫이문(철재, 일반, 양개):DR111-외여닫이문(유리, 일반, 양개) 950x2100mm:7687529:1 - PanelOperation: DOUBLE_ACTING
Type - Pset_DoorCommon - IsExternal: no
OverallHeight: 2100 mm
Pset_DoorCommon - Reference: DR111-외여닫이문(유리, 일반, 양개) 950x2100mm
Pset_QuantityTakeOff - Reference: DR111-외여닫이문(유리, 일반, 양개) 950x2100mm
BaseQuantities - Height: 2100 mm; Width: 950 mm; Area: 1.995 m2
공정 - 생성 공정: 새 구성
구속조건 - 레벨: 지상 1층
기타 - 패밀리: DR111-외여닫이문(철재, 일반, 양개); 유형: DR111-외여닫이문(유리, 일반, 양개) 950x2100mm; 유형 ID: 7685797; 패밀리 및 유형: DR111-외여닫이문(철재, 일반, 양개): DR111-외여닫이문(유리, 일반, 양개) 950x2100mm
치수 - 면적: 2.61395 m2; 벽체 opening 면적: 1.995 m2; 체적: 0.0437082 m3
Name (DR111-외여닫이문(철재, 일반, 양개):DR111-외여닫이문(유리, 일반, 양개) 950x2100mm:...) | OverallWidth (mm) | 마크 | 씰 높이 (mm) | 헤드 높이 (mm) | 호스트 ID
7687529 | 950 | 25UU | -420 | 1680 | 7686358
7689956 | 990 | 25JJJ | 55 | 2155 | 7689655 | Material: <Unnamed>, KBIMS-유리

# IfcDoor: DR111-외여닫이문(철재,일반)_유리포함(원형):DR111-외여닫이문(철재, 일반)_유리포함 (원형)_2100x1000 (10)
Type - OperationType: SINGLE_SWING_LEFT; ParameterTakesPrecedence: no; Sizeable: no; Material: KBIMS-유리, KBIMS-스테인리스 스틸_도금 (10), <Unnamed>
Type - ID 데이터 - OmniClass 번호: 23.30.10.00; OmniClass 제목: Doors; 유형 마크: 86; 유형 이름: DR111-외여닫이문(철재, 일반)_유리포함 (원형)_2100x1000; 유형 해설: SD
Type - 기타 - 카테고리: 문; KBIMS-부위코드: E333; 제작정보: AIBIM-2023; 조달청표준공사코드: ALA; 패밀리 이름: DR111-외여닫이문(철재,일반)_유리포함(원형)
Type - 시공 - 기능: 내부; 벽 마무리: 호스트별
Type - 재료 및 마감재 - 손잡이 재료: KBIMS-스테인리스 스틸_도금; 유리 재료: KBIMS-유리; 유리틀 재료: KBIMS-스테인리스 스틸_도금; 패널 재료: KBIMS-스테인리스 스틸_도금; 프레임 재료: KBIMS-스테인리스 스틸_도금
Type - 치수 - 구조체 간격: 0 mm; A: 0 mm; B: 0 mm; 중심이동: 0 mm; 높이: 2100 mm; 대략적인 높이: 2100 mm; 대략적인 폭: 1000 mm; 두께: 200 mm; 유리_두께: 18 mm; 유리틀_바닥높이: 1300 mm; 유리틀_지름: 400 mm; 유리틀_프레임두께: 50 mm; 유리틀_프레임폭: 20 mm; 패널 두께: 30 mm; 패널 폭: 940 mm; 폭: 1000 mm; 프레임 돌출: 20 mm; 프레임 두께: 200 mm; 프레임 폭: 60 mm; 프레임 홈: 30 mm
Type - 해석 특성 - 열 특성 정의 기준: 개략적 유형; 해석 시공: <없음>
Type - DR111-외여닫이문(철재,일반)_유리포함(원형):DR111-외여닫이문(철재, 일반)_유리포함 (원형)_2100x1000:3171595:1 - PanelOperation: SWINGING
Type - Pset_DoorCommon - IsExternal: no
OverallHeight: 2100 mm; OverallWidth: 1000 mm
Pset_DoorCommon - Reference: DR111-외여닫이문(철재, 일반)_유리포함 (원형)_2100x1000
Pset_QuantityTakeOff - Reference: DR111-외여닫이문(철재, 일반)_유리포함 (원형)_2100x1000
BaseQuantities - Height: 2100 mm; Width: 1000 mm; Area: 2.1 m2
공정 - 생성 공정: 새 구성
기타 - 유형: DR111-외여닫이문(철재, 일반)_유리포함 (원형)_2100x1000; 유형 ID: 7452354; 패밀리: DR111-외여닫이문(철재,일반)_유리포함(원형); 패밀리 및 유형: DR111-외여닫이문(철재,일반)_유리포함(원형): DR111-외여닫이문(철재, 일반)_유리포함 (원형)_2100x1000
치수 - 면적: 3.71966 m2; 체적: 0.116207 m3
Name (DR111-외여닫이문(철재,일반)_유리포함(원형):DR111-외여닫이문(철재, 일반)_유리포함 (원형)_2100x1000:...) | In | 레벨 | 씰 높이 (mm) | 헤드 높이 (mm) | 호스트 ID | Material
3171595 | 지상 2층 | 지상 2층 | 80 | 2180 | 2820060
3171737 | 지상 1층 | 지상 1층 | -470 | 1630 | 2819152 | KBIMS-유리, KBIMS-스테인리스 스틸_도금, <Unnamed>
3171746 | 지상 3층 | 지상 3층 | 80 | 2180 | 2820477 | KBIMS-유리, KBIMS-스테인리스 스틸_도금, <Unnamed>
3171755 | 지상 4층 | 지상 4층 | 80 | 2180 | 2820727 | KBIMS-유리, KBIMS-스테인리스 스틸_도금, <Unnamed>
3171764 | 지상 5층 | 지상 5층 | 80 | 2180 | 2821229 | KBIMS-유리, KBIMS-스테인리스 스틸_도금, <Unnamed>
3171773 | 지상 6층 | 지상 6층 | 80 | 2180 | 2821489 | KBIMS-유리, KBIMS-스테인리스 스틸_도금, <Unnamed>
3171782 | 지상 7층 | 지상 7층 | 80 | 2180 | 2821685 | KBIMS-유리, KBIMS-스테인리스 스틸_도금, <Unnamed>
3171790 | 지상 8층 | 지상 8층 | 80 | 2180 | 2822001 | KBIMS-유리, KBIMS-스테인리스 스틸_도금, <Unnamed>
3171791 | 지상 8층 | 지상 8층 | 80 | 2180 | 2822031 | KBIMS-유리, KBIMS-스테인리스 스틸_도금, <Unnamed>
3171800 | 지상 9층 | 지상 9층 | 80 | 2180 | 2822237 | KBIMS-유리, KBIMS-스테인리스 스틸_도금, <Unnamed>

# IfcDoor: DR111-외여닫이문(철재,일반)_유리포함(원형):DR111-외여닫이문(철재, 일반)_유리포함 (원형)_2100x1000, DR111-외여닫이문(철재,일반)_유리포함(원형):DR111-외여닫이문(철재, 일반)_유리포함 (원형)_2100x1000:3171809
In: 지상 10층
Type - OperationType: SINGLE_SWING_LEFT; ParameterTakesPrecedence: no; Sizeable: no; Material: KBIMS-유리, KBIMS-스테인리스 스틸_도금 (10), <Unnamed>
Type - ID 데이터 - OmniClass 번호: 23.30.10.00; OmniClass 제목: Doors; 유형 마크: 86; 유형 이름: DR111-외여닫이문(철재, 일반)_유리포함 (원형)_2100x1000; 유형 해설: SD
Type - 기타 - 카테고리: 문; KBIMS-부위코드: E333; 제작정보: AIBIM-2023; 조달청표준공사코드: ALA; 패밀리 이름: DR111-외여닫이문(철재,일반)_유리포함(원형)
Type - 시공 - 기능: 내부; 벽 마무리: 호스트별
Type - 재료 및 마감재 - 손잡이 재료: KBIMS-스테인리스 스틸_도금; 유리 재료: KBIMS-유리; 유리틀 재료: KBIMS-스테인리스 스틸_도금; 패널 재료: KBIMS-스테인리스 스틸_도금; 프레임 재료: KBIMS-스테인리스 스틸_도금
Type - 치수 - 구조체 간격: 0 mm; A: 0 mm; B: 0 mm; 중심이동: 0 mm; 높이: 2100 mm; 대략적인 높이: 2100 mm; 대략적인 폭: 1000 mm; 두께: 200 mm; 유리_두께: 18 mm; 유리틀_바닥높이: 1300 mm; 유리틀_지름: 400 mm; 유리틀_프레임두께: 50 mm; 유리틀_프레임폭: 20 mm; 패널 두께: 30 mm; 패널 폭: 940 mm; 폭: 1000 mm; 프레임 돌출: 20 mm; 프레임 두께: 200 mm; 프레임 폭: 60 mm; 프레임 홈: 30 mm
Type - 해석 특성 - 열 특성 정의 기준: 개략적 유형; 해석 시공: <없음>
Type - DR111-외여닫이문(철재,일반)_유리포함(원형):DR111-외여닫이문(철재, 일반)_유리포함 (원형)_2100x1000:3171809:1 - PanelOperation: SWINGING
Type - Pset_DoorCommon - IsExternal: no
OverallHeight: 2100 mm; OverallWidth: 1000 mm
Pset_DoorCommon - Reference: DR111-외여닫이문(철재, 일반)_유리포함 (원형)_2100x1000
Pset_QuantityTakeOff - Reference: DR111-외여닫이문(철재, 일반)_유리포함 (원형)_2100x1000
BaseQuantities - Height: 2100 mm; Width: 1000 mm; Area: 2.1 m2
공정 - 생성 공정: 새 구성
구속조건 - 레벨: 지상 10층; 씰 높이: 80 mm
기타 - 유형: DR111-외여닫이문(철재, 일반)_유리포함 (원형)_2100x1000; 유형 ID: 7452354; 패밀리: DR111-외여닫이문(철재,일반)_유리포함(원형); 패밀리 및 유형: DR111-외여닫이문(철재,일반)_유리포함(원형): DR111-외여닫이문(철재, 일반)_유리포함 (원형)_2100x1000; 헤드 높이: 2180 mm; 호스트 ID: 2822423
치수 - 면적: 3.71966 m2; 체적: 0.116207 m3

# IfcDoor: DR111-외여닫이문(철재,일반)_유리포함(원형):DR111-외여닫이문(철재, 일반)_유리포함 (원형)_2100x1000 (8)
Type - OperationType: SINGLE_SWING_RIGHT; ParameterTakesPrecedence: no; Sizeable: no; Material: KBIMS-유리, KBIMS-스테인리스 스틸_도금 (10), <Unnamed>
Type - DR111-외여닫이문(철재,일반)_유리포함(원형):DR111-외여닫이문(철재, 일반)_유리포함 (원형)_2100x1000:3171448:1 - PanelOperation: SWINGING
Type - ID 데이터 - OmniClass 번호: 23.30.10.00; OmniClass 제목: Doors; 유형 마크: 86; 유형 이름: DR111-외여닫이문(철재, 일반)_유리포함 (원형)_2100x1000; 유형 해설: SD
Type - 기타 - 카테고리: 문; KBIMS-부위코드: E333; 제작정보: AIBIM-2023; 조달청표준공사코드: ALA; 패밀리 이름: DR111-외여닫이문(철재,일반)_유리포함(원형)
Type - 시공 - 기능: 내부; 벽 마무리: 호스트별
Type - 재료 및 마감재 - 손잡이 재료: KBIMS-스테인리스 스틸_도금; 유리 재료: KBIMS-유리; 유리틀 재료: KBIMS-스테인리스 스틸_도금; 패널 재료: KBIMS-스테인리스 스틸_도금; 프레임 재료: KBIMS-스테인리스 스틸_도금
Type - 치수 - 구조체 간격: 0 mm; A: 0 mm; B: 0 mm; 중심이동: 0 mm; 높이: 2100 mm; 대략적인 높이: 2100 mm; 대략적인 폭: 1000 mm; 두께: 200 mm; 유리_두께: 18 mm; 유리틀_바닥높이: 1300 mm; 유리틀_지름: 400 mm; 유리틀_프레임두께: 50 mm; 유리틀_프레임폭: 20 mm; 패널 두께: 30 mm; 패널 폭: 940 mm; 폭: 1000 mm; 프레임 돌출: 20 mm; 프레임 두께: 200 mm; 프레임 폭: 60 mm; 프레임 홈: 30 mm
Type - 해석 특성 - 열 특성 정의 기준: 개략적 유형; 해석 시공: <없음>
Type - Pset_DoorCommon - IsExternal: no
OverallHeight: 2100 mm; OverallWidth: 1000 mm
Pset_DoorCommon - Reference: DR111-외여닫이문(철재, 일반)_유리포함 (원형)_2100x1000
Pset_QuantityTakeOff - Reference: DR111-외여닫이문(철재, 일반)_유리포함 (원형)_2100x1000
BaseQuantities - Height: 2100 mm; Width: 1000 mm; Area: 2.1 m2
공정 - 생성 공정: 새 구성
기타 - 유형: DR111-외여닫이문(철재, 일반)_유리포함 (원형)_2100x1000; 유형 ID: 7452354; 패밀리: DR111-외여닫이문(철재,일반)_유리포함(원형); 패밀리 및 유형: DR111-외여닫이문(철재,일반)_유리포함(원형): DR111-외여닫이문(철재, 일반)_유리포함 (원형)_2100x1000
치수 - 면적: 3.71966 m2; 체적: 0.116207 m3
Name (DR111-외여닫이문(철재,일반)_유리포함(원형):DR111-외여닫이문(철재, 일반)_유리포함 (원형)_2100x1000:...) | In | 레벨 | 씰 높이 (mm) | 헤드 높이 (mm) | 호스트 ID | Material
3171448 | 지상 2층 | 지상 2층 | 80 | 2180 | 2820028
3171736 | 지상 1층 | 지상 1층 | -470 | 1630 | 2818043 | KBIMS-유리, KBIMS-스테인리스 스틸_도금, <Unnamed>
3171745 | 지상 3층 | 지상 3층 | 80 | 2180 | 2820447 | KBIMS-유리, KBIMS-스테인리스 스틸_도금, <Unnamed>
3171754 | 지상 4층 | 지상 4층 | 80 | 2180 | 2820697 | KBIMS-유리, KBIMS-스테인리스 스틸_도금, <Unnamed>
3171763 | 지상 5층 | 지상 5층 | 80 | 2180 | 2821199 | KBIMS-유리, KBIMS-스테인리스 스틸_도금, <Unnamed>
3171772 | 지상 6층 | 지상 6층 | 80 | 2180 | 2821459 | KBIMS-유리, KBIMS-스테인리스 스틸_도금, <Unnamed>
3171781 | 지상 7층 | 지상 7층 | 80 | 2180 | 2821655 | KBIMS-유리, KBIMS-스테인리스 스틸_도금, <Unnamed>
3171799 | 지상 9층 | 지상 9층 | 80 | 2180 | 2822207 | KBIMS-유리, KBIMS-스테인리스 스틸_도금, <Unnamed>

# IfcDoor: DR111-외여닫이문(철재,일반)_유리포함(원형):DR111-외여닫이문(철재, 일반)_유리포함 (원형)_2100x1000, DR111-외여닫이문(철재,일반)_유리포함(원형):DR111-외여닫이문(철재, 일반)_유리포함 (원형)_2100x1000:3171808
In: 지상 10층
Type - OperationType: SINGLE_SWING_RIGHT; ParameterTakesPrecedence: no; Sizeable: no; Material: KBIMS-유리, KBIMS-스테인리스 스틸_도금 (10), <Unnamed>
Type - ID 데이터 - OmniClass 번호: 23.30.10.00; OmniClass 제목: Doors; 유형 마크: 86; 유형 이름: DR111-외여닫이문(철재, 일반)_유리포함 (원형)_2100x1000; 유형 해설: SD
Type - 기타 - 카테고리: 문; KBIMS-부위코드: E333; 제작정보: AIBIM-2023; 조달청표준공사코드: ALA; 패밀리 이름: DR111-외여닫이문(철재,일반)_유리포함(원형)
Type - 시공 - 기능: 내부; 벽 마무리: 호스트별
Type - 재료 및 마감재 - 손잡이 재료: KBIMS-스테인리스 스틸_도금; 유리 재료: KBIMS-유리; 유리틀 재료: KBIMS-스테인리스 스틸_도금; 패널 재료: KBIMS-스테인리스 스틸_도금; 프레임 재료: KBIMS-스테인리스 스틸_도금
Type - 치수 - 구조체 간격: 0 mm; A: 0 mm; B: 0 mm; 중심이동: 0 mm; 높이: 2100 mm; 대략적인 높이: 2100 mm; 대략적인 폭: 1000 mm; 두께: 200 mm; 유리_두께: 18 mm; 유리틀_바닥높이: 1300 mm; 유리틀_지름: 400 mm; 유리틀_프레임두께: 50 mm; 유리틀_프레임폭: 20 mm; 패널 두께: 30 mm; 패널 폭: 940 mm; 폭: 1000 mm; 프레임 돌출: 20 mm; 프레임 두께: 200 mm; 프레임 폭: 60 mm; 프레임 홈: 30 mm
Type - 해석 특성 - 열 특성 정의 기준: 개략적 유형; 해석 시공: <없음>
Type - DR111-외여닫이문(철재,일반)_유리포함(원형):DR111-외여닫이문(철재, 일반)_유리포함 (원형)_2100x1000:3171808:1 - PanelOperation: SWINGING
Type - Pset_DoorCommon - IsExternal: no
OverallHeight: 2100 mm; OverallWidth: 1000 mm
Pset_DoorCommon - Reference: DR111-외여닫이문(철재, 일반)_유리포함 (원형)_2100x1000
Pset_QuantityTakeOff - Reference: DR111-외여닫이문(철재, 일반)_유리포함 (원형)_2100x1000
BaseQuantities - Height: 2100 mm; Width: 1000 mm; Area: 2.1 m2
공정 - 생성 공정: 새 구성
구속조건 - 레벨: 지상 10층; 씰 높이: 80 mm
기타 - 유형: DR111-외여닫이문(철재, 일반)_유리포함 (원형)_2100x1000; 유형 ID: 7452354; 패밀리: DR111-외여닫이문(철재,일반)_유리포함(원형); 패밀리 및 유형: DR111-외여닫이문(철재,일반)_유리포함(원형): DR111-외여닫이문(철재, 일반)_유리포함 (원형)_2100x1000; 헤드 높이: 2180 mm; 호스트 ID: 7720241
치수 - 면적: 3.71966 m2; 체적: 0.116207 m3

# IfcDoor: DR120-쌍여닫이문:DR120-쌍여닫이문 (4)
In: 지상 1층
Type - OperationType: DOUBLE_DOOR_SINGLE_SWING; ParameterTakesPrecedence: no; Sizeable: no; Material: <Unnamed> (16), 유리 (3)
Type - DR120-쌍여닫이문:DR120-쌍여닫이문:7678364:1 - PanelOperation: SWINGING
Type - ID 데이터 - OmniClass 번호: 23.30.10.00; OmniClass 제목: Doors; 유형 마크: 95; 유형 이름: DR120-쌍여닫이문; 유형 해설: SD
Type - 기타 - 카테고리: 문; 성능-도장포함 여부: no; 성능-유리포함 여부: no; 주출입구여부: yes; KBIMS_보급정보-보급코드: bSK-191231; KBIMS_보급정보-저작자: (사)빌딩스마트협회; KBIMS_식별-버전: 1.03; KBIMS-부위코드: E333; 건설정보분류체계-부위분류: E333; 조달청표준공사코드: ALA; 조달청표준공사코드-세부공종: ALA; 패밀리 이름: DR120-쌍여닫이문
Type - 시공 - 기능: 내부; 벽 마무리: 호스트별
Type - 재료 및 마감재 - 문패널 재료: 유리; 문프레임 재료: 유리
Type - 치수 - 대략적인 높이: 0 mm; 대략적인 폭: 0 mm; 두께: 0 mm; 높이: 2100 mm; 문패널 두께: 15 mm; 문프레임 돌출 두께: 0 mm; 문프레임 폭: 30 mm; 패널 폭: 860 mm; 폭: 1750 mm
Type - 해석 특성 - 열 특성 정의 기준: 개략적 유형; 해석 시공: <없음>
Type - Pset_DoorCommon - IsExternal: no
OverallHeight: 2100 mm
Pset_DoorCommon - Reference: DR120-쌍여닫이문
Pset_QuantityTakeOff - Reference: DR120-쌍여닫이문
BaseQuantities - Height: 2100 mm; Width: 1750 mm; Area: 3.675 m2
공정 - 생성 공정: 새 구성
구속조건 - 레벨: 지상 1층
기타 - 유형: DR120-쌍여닫이문; 유형 ID: 7678345; 패밀리: DR120-쌍여닫이문; 패밀리 및 유형: DR120-쌍여닫이문: DR120-쌍여닫이문
데이터 - 벽체 opening 면적: 3.675 m2
치수 - 면적: 4.49935 m2; 체적: 0.0705172 m3
Name (DR120-쌍여닫이문:DR120-쌍여닫이문:...) | OverallWidth (mm) | 마크 | 씰 높이 (mm) | 헤드 높이 (mm) | 호스트 ID | Material
7678364 | 2535 | 25JJ | 55 | 2155 | 7676584
7678817 | 1750 | 25KK | 55 | 2155 | 7678814 | <Unnamed>, 유리
7687815 | 1750 | 25VV | -420 | 1680 | 7687806 | <Unnamed>, 유리
7687873 | 1750 | 25WW | -420 | 1680 | 7687809 | <Unnamed>, 유리

# IfcDoor: DR121-쌍여닫이문(철재, 방화문):DR121-쌍여닫이문(철재, 방화문) 1800x2100mm (11)
Type - OperationType: DOUBLE_DOOR_SINGLE_SWING; ParameterTakesPrecedence: no; Sizeable: no; Material: <Unnamed> (16), KBIMS-철재 (2), KBIMS-철재 프레임
Type - ID 데이터(Type) - OmniClass 번호: 23.30.10.00; OmniClass 제목: Doors; 유형 마크: 55; 유형 이름: DR121-쌍여닫이문(철재, 방화문) 1800x2100mm; 유형 해설: FSD
Type - 기타(Type) - 카테고리: 문; KBIMS_보급정보-보급코드: bSK-191231; KBIMS_보급정보-저작자: (사)빌딩스마트협회; KBIMS_식별-버전: 1.03; KBIMS-부위코드: E333; 건설정보분류체계-부위분류: E333; 성능-도장포함 여부: no; 성능-방화등급: 갑종; 성능-유리포함 여부: no; 제작정보: AIBIM-2023; 조달청표준공사코드: ALA110300000; 조달청표준공사코드-세부공종: ALA110303000; 패밀리 이름: DR121-쌍여닫이문(철재, 방화문)
Type - 시공(Type) - 기능: 내부; 벽 마무리: 호스트별
Type - 재료 및 마감재(Type) - 문패널 재료: KBIMS-철재; 문프레임 재료: KBIMS-철재 프레임
Type - 치수(Type) - 높이: 2100 mm; 대략적인 높이: 0 mm; 대략적인 폭: 0 mm; 두께: 0 mm; 문패널 두께: 25 mm; 문프레임 돌출 두께: 20 mm; 문프레임 폭: 50 mm; 패널 폭: 875 mm; 폭: 1800 mm
Type - 해석 특성(Type) - 열 특성 정의 기준: 개략적 유형; 해석 시공: <없음>
Type - DR121-쌍여닫이문(철재, 방화문):DR121-쌍여닫이문(철재, 방화문) 1800x2100mm:3047872:1 - PanelOperation: SWINGING
Type - Pset_DoorCommon - IsExternal: no
OverallHeight: 2100 mm; OverallWidth: 1800 mm
Pset_DoorCommon - Reference: DR121-쌍여닫이문(철재, 방화문) 1800x2100mm
Pset_QuantityTakeOff - Reference: DR121-쌍여닫이문(철재, 방화문) 1800x2100mm
BaseQuantities - Height: 2100 mm; Width: 1800 mm; Area: 3.78 m2
공정 - 생성 공정: 새 구성
기타 - 유형: DR121-쌍여닫이문(철재, 방화문) 1800x2100mm; 유형 ID: 7435628; 카테고리: 문; 패밀리: DR121-쌍여닫이문(철재, 방화문); 패밀리 및 유형: DR121-쌍여닫이문(철재, 방화문): DR121-쌍여닫이문(철재, 방화문) 1800x2100mm
데이터 - 벽체 opening 면적: 3.78 m2
치수 - 면적: 5.32025 m2; 체적: 0.146498 m3
Name (DR121-쌍여닫이문(철재, 방화문):DR121-쌍여닫이문(철재, 방화문) 1800x2100mm:...) | In | 레벨 | 씰 높이 (mm) | 헤드 높이 (mm) | 호스트 ID | Material
3047872 | 지하2층 | 지하2층 | 200 | 2300 | 2813275
3048116 | 지하2층 | 지하2층 | 200 | 2300 | 2814153 | <Unnamed>, KBIMS-철재, KBIMS-철재 프레임
3054000 | 지하1층 | 지하1층 | 200 | 2300 | 2816463 | <Unnamed>, KBIMS-철재, KBIMS-철재 프레임
3081811 | 지상 2층 | 지상 2층 | 80 | 2180 | 2820050 | <Unnamed>, KBIMS-철재, KBIMS-철재 프레임
3081917 | 지상 3층 | 지상 3층 | 80 | 2180 | 2820467 | <Unnamed>, KBIMS-철재, KBIMS-철재 프레임
3081923 | 지상 4층 | 지상 4층 | 80 | 2180 | 2820717 | <Unnamed>, KBIMS-철재, KBIMS-철재 프레임
3081929 | 지상 5층 | 지상 5층 | 80 | 2180 | 2821219 | <Unnamed>, KBIMS-철재, KBIMS-철재 프레임
3081935 | 지상 6층 | 지상 6층 | 80 | 2180 | 2821479 | <Unnamed>, KBIMS-철재, KBIMS-철재 프레임
3081941 | 지상 7층 | 지상 7층 | 80 | 2180 | 2821675 | <Unnamed>, KBIMS-철재, KBIMS-철재 프레임
3081947 | 지상 8층 | 지상 8층 | 80 | 2180 | 2822021 | <Unnamed>, KBIMS-철재, KBIMS-철재 프레임
3081953 | 지상 9층 | 지상 9층 | 80 | 2180 | 2822227 | <Unnamed>, KBIMS-철재, KBIMS-철재 프레임

# IfcDoor: DR121-쌍여닫이문(철재, 방화문):DR121-쌍여닫이문(철재, 방화문) 1800x2100mm (4)
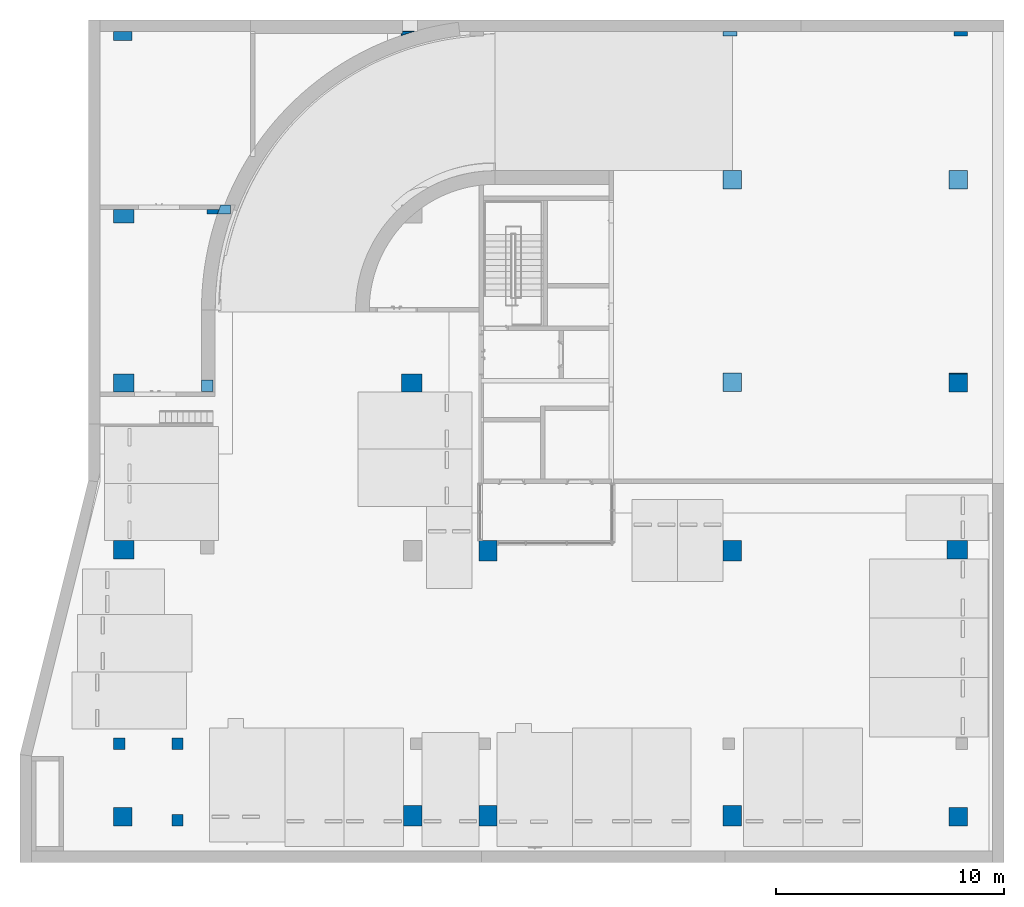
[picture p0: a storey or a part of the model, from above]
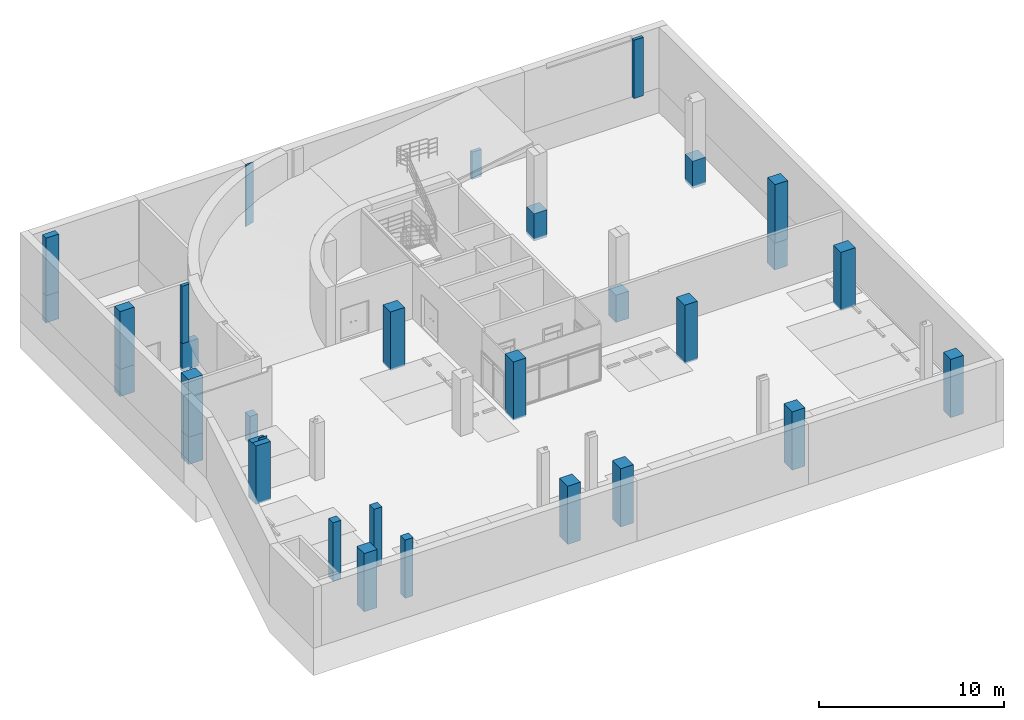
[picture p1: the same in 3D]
Properties of the parts of a building model (IFC2X3), part 12 of 39

# IfcDoor: DR121-쌍여닫이문(철재, 방화문):DR121-쌍여닫이문(철재, 방화문) 1800x2100mm (4)
Type - OperationType: DOUBLE_DOOR_SINGLE_SWING; ParameterTakesPrecedence: no; Sizeable: no; Material: <Unnamed> (16), KBIMS-철재 (2), KBIMS-철재 프레임
Type - ID 데이터(Type) - OmniClass 번호: 23.30.10.00; OmniClass 제목: Doors; 유형 마크: 55; 유형 이름: DR121-쌍여닫이문(철재, 방화문) 1800x2100mm; 유형 해설: FSD
Type - 기타(Type) - 카테고리: 문; KBIMS_보급정보-보급코드: bSK-191231; KBIMS_보급정보-저작자: (사)빌딩스마트협회; KBIMS_식별-버전: 1.03; KBIMS-부위코드: E333; 건설정보분류체계-부위분류: E333; 성능-도장포함 여부: no; 성능-방화등급: 갑종; 성능-유리포함 여부: no; 제작정보: AIBIM-2023; 조달청표준공사코드: ALA110300000; 조달청표준공사코드-세부공종: ALA110303000; 패밀리 이름: DR121-쌍여닫이문(철재, 방화문)
Type - 시공(Type) - 기능: 내부; 벽 마무리: 호스트별
Type - 재료 및 마감재(Type) - 문패널 재료: KBIMS-철재; 문프레임 재료: KBIMS-철재 프레임
Type - 치수(Type) - 높이: 2100 mm; 대략적인 높이: 0 mm; 대략적인 폭: 0 mm; 두께: 0 mm; 문패널 두께: 25 mm; 문프레임 돌출 두께: 20 mm; 문프레임 폭: 50 mm; 패널 폭: 875 mm; 폭: 1800 mm
Type - 해석 특성(Type) - 열 특성 정의 기준: 개략적 유형; 해석 시공: <없음>
Type - DR121-쌍여닫이문(철재, 방화문):DR121-쌍여닫이문(철재, 방화문) 1800x2100mm:3048500:1 - PanelOperation: SWINGING
Type - Pset_DoorCommon - IsExternal: no
OverallHeight: 2100 mm; OverallWidth: 1800 mm
Pset_DoorCommon - Reference: DR121-쌍여닫이문(철재, 방화문) 1800x2100mm
Pset_QuantityTakeOff - Reference: DR121-쌍여닫이문(철재, 방화문) 1800x2100mm
BaseQuantities - Height: 2100 mm; Width: 1800 mm; Area: 3.78 m2
공정 - 생성 공정: 새 구성
구속조건 - 씰 높이: 160 mm
기타 - 유형: DR121-쌍여닫이문(철재, 방화문) 1800x2100mm; 유형 ID: 7435628; 카테고리: 문; 패밀리: DR121-쌍여닫이문(철재, 방화문); 패밀리 및 유형: DR121-쌍여닫이문(철재, 방화문): DR121-쌍여닫이문(철재, 방화문) 1800x2100mm; 헤드 높이: 2260 mm
데이터 - 벽체 opening 면적: 3.78 m2
치수 - 면적: 5.32025 m2; 체적: 0.146498 m3
Name (DR121-쌍여닫이문(철재, 방화문):DR121-쌍여닫이문(철재, 방화문) 1800x2100mm:...) | In | 레벨 | 호스트 ID | Material
3048500 | 지하2층 | PIT | 2815051
3054797 | 지하1층 | 지하1층 | 2816493 | <Unnamed>, KBIMS-철재, KBIMS-철재 프레임
3054927 | 지하1층 | 지하1층 | 2816491 | <Unnamed>, KBIMS-철재, KBIMS-철재 프레임
3154184 | 지하2층 | PIT | 2815303 | <Unnamed>, KBIMS-철재, KBIMS-철재 프레임

# IfcDoor: DR121-쌍여닫이문(철재, 방화문):DR121-쌍여닫이문(철재, 방화문) 1800x2100mm, DR121-쌍여닫이문(철재, 방화문):DR121-쌍여닫이문(철재, 방화문) 1800x2100mm:3054616
In: 지하1층
Type - OperationType: DOUBLE_DOOR_SINGLE_SWING; ParameterTakesPrecedence: no; Sizeable: no; Material: <Unnamed> (16), KBIMS-철재 (2), KBIMS-철재 프레임
Type - ID 데이터(Type) - OmniClass 번호: 23.30.10.00; OmniClass 제목: Doors; 유형 마크: 55; 유형 이름: DR121-쌍여닫이문(철재, 방화문) 1800x2100mm; 유형 해설: FSD
Type - 기타(Type) - 카테고리: 문; KBIMS_보급정보-보급코드: bSK-191231; KBIMS_보급정보-저작자: (사)빌딩스마트협회; KBIMS_식별-버전: 1.03; KBIMS-부위코드: E333; 건설정보분류체계-부위분류: E333; 성능-도장포함 여부: no; 성능-방화등급: 갑종; 성능-유리포함 여부: no; 제작정보: AIBIM-2023; 조달청표준공사코드: ALA110300000; 조달청표준공사코드-세부공종: ALA110303000; 패밀리 이름: DR121-쌍여닫이문(철재, 방화문)
Type - 시공(Type) - 기능: 내부; 벽 마무리: 호스트별
Type - 재료 및 마감재(Type) - 문패널 재료: KBIMS-철재; 문프레임 재료: KBIMS-철재 프레임
Type - 치수(Type) - 높이: 2100 mm; 대략적인 높이: 0 mm; 대략적인 폭: 0 mm; 두께: 0 mm; 문패널 두께: 25 mm; 문프레임 돌출 두께: 20 mm; 문프레임 폭: 50 mm; 패널 폭: 875 mm; 폭: 1800 mm
Type - 해석 특성(Type) - 열 특성 정의 기준: 개략적 유형; 해석 시공: <없음>
Type - DR121-쌍여닫이문(철재, 방화문):DR121-쌍여닫이문(철재, 방화문) 1800x2100mm:3054616:1 - PanelOperation: SWINGING
Type - Pset_DoorCommon - IsExternal: no
OverallHeight: 2100 mm; OverallWidth: 1800 mm
Pset_DoorCommon - Reference: DR121-쌍여닫이문(철재, 방화문) 1800x2100mm
Pset_QuantityTakeOff - Reference: DR121-쌍여닫이문(철재, 방화문) 1800x2100mm
BaseQuantities - Height: 2100 mm; Width: 1800 mm; Area: 3.78 m2
공정 - 생성 공정: 새 구성
구속조건 - 레벨: 지하1층; 씰 높이: 200 mm
기타 - 유형: DR121-쌍여닫이문(철재, 방화문) 1800x2100mm; 유형 ID: 7435628; 카테고리: 문; 패밀리: DR121-쌍여닫이문(철재, 방화문); 패밀리 및 유형: DR121-쌍여닫이문(철재, 방화문): DR121-쌍여닫이문(철재, 방화문) 1800x2100mm; 헤드 높이: 2300 mm; 호스트 ID: 2816483
데이터 - 벽체 opening 면적: 3.78 m2
치수 - 면적: 5.32025 m2; 체적: 0.146498 m3

# IfcDoor: DR121-쌍여닫이문(철재, 방화문):DR121-쌍여닫이문(철재, 방화문) 1800x2100mm, DR121-쌍여닫이문(철재, 방화문):DR121-쌍여닫이문(철재, 방화문) 1800x2100mm:3081959
In: 지상 10층
Type - OperationType: DOUBLE_DOOR_SINGLE_SWING; ParameterTakesPrecedence: no; Sizeable: no; Material: <Unnamed> (16), KBIMS-철재 (2), KBIMS-철재 프레임
Type - ID 데이터(Type) - OmniClass 번호: 23.30.10.00; OmniClass 제목: Doors; 유형 마크: 55; 유형 이름: DR121-쌍여닫이문(철재, 방화문) 1800x2100mm; 유형 해설: FSD
Type - 기타(Type) - 카테고리: 문; KBIMS_보급정보-보급코드: bSK-191231; KBIMS_보급정보-저작자: (사)빌딩스마트협회; KBIMS_식별-버전: 1.03; KBIMS-부위코드: E333; 건설정보분류체계-부위분류: E333; 성능-도장포함 여부: no; 성능-방화등급: 갑종; 성능-유리포함 여부: no; 제작정보: AIBIM-2023; 조달청표준공사코드: ALA110300000; 조달청표준공사코드-세부공종: ALA110303000; 패밀리 이름: DR121-쌍여닫이문(철재, 방화문)
Type - 시공(Type) - 기능: 내부; 벽 마무리: 호스트별
Type - 재료 및 마감재(Type) - 문패널 재료: KBIMS-철재; 문프레임 재료: KBIMS-철재 프레임
Type - 치수(Type) - 높이: 2100 mm; 대략적인 높이: 0 mm; 대략적인 폭: 0 mm; 두께: 0 mm; 문패널 두께: 25 mm; 문프레임 돌출 두께: 20 mm; 문프레임 폭: 50 mm; 패널 폭: 875 mm; 폭: 1800 mm
Type - 해석 특성(Type) - 열 특성 정의 기준: 개략적 유형; 해석 시공: <없음>
Type - DR121-쌍여닫이문(철재, 방화문):DR121-쌍여닫이문(철재, 방화문) 1800x2100mm:3081959:1 - PanelOperation: SWINGING
Type - Pset_DoorCommon - IsExternal: no
OverallHeight: 2100 mm; OverallWidth: 1800 mm
Pset_DoorCommon - Reference: DR121-쌍여닫이문(철재, 방화문) 1800x2100mm
Pset_QuantityTakeOff - Reference: DR121-쌍여닫이문(철재, 방화문) 1800x2100mm
BaseQuantities - Height: 2100 mm; Width: 1800 mm; Area: 3.78 m2
공정 - 생성 공정: 새 구성
구속조건 - 레벨: 지상 10층; 씰 높이: 80 mm
기타 - 유형: DR121-쌍여닫이문(철재, 방화문) 1800x2100mm; 유형 ID: 7435628; 카테고리: 문; 패밀리: DR121-쌍여닫이문(철재, 방화문); 패밀리 및 유형: DR121-쌍여닫이문(철재, 방화문): DR121-쌍여닫이문(철재, 방화문) 1800x2100mm; 헤드 높이: 2180 mm; 호스트 ID: 2822413
데이터 - 벽체 opening 면적: 3.78 m2
치수 - 면적: 5.53445 m2; 체적: 0.157118 m3

# IfcDoor: DR121-쌍여닫이문(철재, 방화문):DR121-쌍여닫이문(철재, 방화문) 1800x2100mm, DR121-쌍여닫이문(철재, 방화문):DR121-쌍여닫이문(철재, 방화문) 1800x2100mm:3094399
In: 옥탑층
Type - OperationType: DOUBLE_DOOR_SINGLE_SWING; ParameterTakesPrecedence: no; Sizeable: no; Material: <Unnamed> (16), KBIMS-철재 (2), KBIMS-철재 프레임
Type - ID 데이터(Type) - OmniClass 번호: 23.30.10.00; OmniClass 제목: Doors; 유형 마크: 55; 유형 이름: DR121-쌍여닫이문(철재, 방화문) 1800x2100mm; 유형 해설: FSD
Type - 기타(Type) - 카테고리: 문; KBIMS_보급정보-보급코드: bSK-191231; KBIMS_보급정보-저작자: (사)빌딩스마트협회; KBIMS_식별-버전: 1.03; KBIMS-부위코드: E333; 건설정보분류체계-부위분류: E333; 성능-도장포함 여부: no; 성능-방화등급: 갑종; 성능-유리포함 여부: no; 제작정보: AIBIM-2023; 조달청표준공사코드: ALA110300000; 조달청표준공사코드-세부공종: ALA110303000; 패밀리 이름: DR121-쌍여닫이문(철재, 방화문)
Type - 시공(Type) - 기능: 내부; 벽 마무리: 호스트별
Type - 재료 및 마감재(Type) - 문패널 재료: KBIMS-철재; 문프레임 재료: KBIMS-철재 프레임
Type - 치수(Type) - 높이: 2100 mm; 대략적인 높이: 0 mm; 대략적인 폭: 0 mm; 두께: 0 mm; 문패널 두께: 25 mm; 문프레임 돌출 두께: 20 mm; 문프레임 폭: 50 mm; 패널 폭: 875 mm; 폭: 1800 mm
Type - 해석 특성(Type) - 열 특성 정의 기준: 개략적 유형; 해석 시공: <없음>
Type - DR121-쌍여닫이문(철재, 방화문):DR121-쌍여닫이문(철재, 방화문) 1800x2100mm:3094399:1 - PanelOperation: SWINGING
Type - Pset_DoorCommon - IsExternal: no
OverallHeight: 2100 mm; OverallWidth: 1800 mm
Pset_DoorCommon - Reference: DR121-쌍여닫이문(철재, 방화문) 1800x2100mm
Pset_QuantityTakeOff - Reference: DR121-쌍여닫이문(철재, 방화문) 1800x2100mm
BaseQuantities - Height: 2100 mm; Width: 1800 mm; Area: 3.78 m2
공정 - 생성 공정: 새 구성
구속조건 - 레벨: 옥탑층; 씰 높이: 80 mm
기타 - 유형: DR121-쌍여닫이문(철재, 방화문) 1800x2100mm; 유형 ID: 7435628; 카테고리: 문; 패밀리: DR121-쌍여닫이문(철재, 방화문); 패밀리 및 유형: DR121-쌍여닫이문(철재, 방화문): DR121-쌍여닫이문(철재, 방화문) 1800x2100mm; 호스트 ID: 2822815; 헤드 높이: 2180 mm
데이터 - 벽체 opening 면적: 3.78 m2
치수 - 면적: 5.32025 m2; 체적: 0.146498 m3

# IfcDoor: DR121-쌍여닫이문(철재, 일반, 양개):DR121-쌍여닫이문(유리, 일반, 양개) 1450x2100mm 2, DR121-쌍여닫이문(철재, 일반, 양개):DR121-쌍여닫이문(유리, 일반, 양개) 1450x2100mm 2:7696018
In: 지상 4층
Type - OperationType: DOUBLE_DOOR_DOUBLE_SWING; ParameterTakesPrecedence: no; Sizeable: no; Material: KBIMS-철재 프레임 (4), 유리 (3)
Type - DR121-쌍여닫이문(철재, 일반, 양개):DR121-쌍여닫이문(유리, 일반, 양개) 1450x2100mm 2:7696018:1 - PanelOperation: DOUBLE_ACTING
Type - ID 데이터 - OmniClass 번호: 23.30.10.00; OmniClass 제목: Doors; 유형 마크: 134; 유형 이름: DR121-쌍여닫이문(유리, 일반, 양개) 1450x2100mm 2; 유형 해설: SD
Type - 기타 - 카테고리: 문; 성능-도장포함 여부: no; 성능-유리포함 여부: no; KBIMS_보급정보-보급코드: bSK-191231; KBIMS_보급정보-저작자: (사)빌딩스마트협회; KBIMS_식별-버전: 1.03; KBIMS-부위코드: E333; 건설정보분류체계-부위분류: E333; 조달청표준공사코드: ALA110300000; 조달청표준공사코드-세부공종: ALA120319000A; 패밀리 이름: DR121-쌍여닫이문(철재, 일반, 양개)
Type - 시공 - 기능: 내부; 벽 마무리: 호스트별
Type - 재료 및 마감재 - 문패널 재료: 유리; 문프레임 재료: 유리
Type - 치수 - 대략적인 높이: 0 mm; 대략적인 폭: 0 mm; 두께: 0 mm; 내부 문프레임 돌출 두께: 10 mm; 높이: 2100 mm; 문패널 두께: 15 mm; 문프레임 폭: 30 mm; 외부 문프레임 돌출 두께: 10 mm; 패널 폭: 695 mm; 폭: 1450 mm
Type - 해석 특성 - 열 특성 정의 기준: 개략적 유형; 해석 시공: <없음>
Type - Pset_DoorCommon - IsExternal: no
OverallHeight: 2100 mm; OverallWidth: 1450 mm
Pset_DoorCommon - Reference: DR121-쌍여닫이문(유리, 일반, 양개) 1450x2100mm 2
Pset_QuantityTakeOff - Reference: DR121-쌍여닫이문(유리, 일반, 양개) 1450x2100mm 2
BaseQuantities - Height: 2100 mm; Width: 1450 mm; Area: 3.045 m2
ID 데이터 - 마크: 25EEEE
공정 - 생성 공정: 새 구성
구속조건 - 레벨: 지상 4층; 씰 높이: 55 mm
기타 - 패밀리: DR121-쌍여닫이문(철재, 일반, 양개); 유형: DR121-쌍여닫이문(유리, 일반, 양개) 1450x2100mm 2; 유형 ID: 7696360; 패밀리 및 유형: DR121-쌍여닫이문(철재, 일반, 양개): DR121-쌍여닫이문(유리, 일반, 양개) 1450x2100mm 2; 헤드 높이: 2155 mm; 호스트 ID: 7695931
데이터 - 벽체 opening 면적: 3.045 m2
치수 - 면적: 3.73165 m2; 체적: 0.060295 m3

# IfcDoor: DR121-쌍여닫이문(철재, 일반, 양개):DR121-쌍여닫이문(유리, 일반, 양개) 1450x2100mm 2 (4)
Type - OperationType: DOUBLE_DOOR_DOUBLE_SWING; ParameterTakesPrecedence: no; Sizeable: no; Material: KBIMS-철재 프레임 (4), 유리 (3)
Type - ID 데이터 - OmniClass 번호: 23.30.10.00; OmniClass 제목: Doors; 유형 마크: 134; 유형 이름: DR121-쌍여닫이문(유리, 일반, 양개) 1450x2100mm 2; 유형 해설: SD
Type - 기타 - 카테고리: 문; 성능-도장포함 여부: no; 성능-유리포함 여부: no; KBIMS_보급정보-보급코드: bSK-191231; KBIMS_보급정보-저작자: (사)빌딩스마트협회; KBIMS_식별-버전: 1.03; KBIMS-부위코드: E333; 건설정보분류체계-부위분류: E333; 조달청표준공사코드: ALA110300000; 조달청표준공사코드-세부공종: ALA120319000A; 패밀리 이름: DR121-쌍여닫이문(철재, 일반, 양개)
Type - 시공 - 기능: 내부; 벽 마무리: 호스트별
Type - 재료 및 마감재 - 문패널 재료: 유리; 문프레임 재료: 유리
Type - 치수 - 대략적인 높이: 0 mm; 대략적인 폭: 0 mm; 두께: 0 mm; 내부 문프레임 돌출 두께: 10 mm; 높이: 2100 mm; 문패널 두께: 15 mm; 문프레임 폭: 30 mm; 외부 문프레임 돌출 두께: 10 mm; 패널 폭: 695 mm; 폭: 1450 mm
Type - 해석 특성 - 열 특성 정의 기준: 개략적 유형; 해석 시공: <없음>
Type - DR121-쌍여닫이문(철재, 일반, 양개):DR121-쌍여닫이문(유리, 일반, 양개) 1450x2100mm 2:7696411:1 - PanelOperation: DOUBLE_ACTING
Type - Pset_DoorCommon - IsExternal: no
OverallHeight: 2100 mm; OverallWidth: 1450 mm
Pset_DoorCommon - Reference: DR121-쌍여닫이문(유리, 일반, 양개) 1450x2100mm 2
Pset_QuantityTakeOff - Reference: DR121-쌍여닫이문(유리, 일반, 양개) 1450x2100mm 2
BaseQuantities - Height: 2100 mm; Width: 1450 mm; Area: 3.045 m2
공정 - 생성 공정: 새 구성
구속조건 - 씰 높이: 55 mm
기타 - 패밀리: DR121-쌍여닫이문(철재, 일반, 양개); 유형: DR121-쌍여닫이문(유리, 일반, 양개) 1450x2100mm 2; 유형 ID: 7696360; 패밀리 및 유형: DR121-쌍여닫이문(철재, 일반, 양개): DR121-쌍여닫이문(유리, 일반, 양개) 1450x2100mm 2; 헤드 높이: 2155 mm
데이터 - 벽체 opening 면적: 3.045 m2
치수 - 면적: 3.67545 m2; 체적: 0.058618 m3
Name (DR121-쌍여닫이문(철재, 일반, 양개):DR121-쌍여닫이문(유리, 일반, 양개) 1450x2100mm 2:...) | In | 마크 | 레벨 | 호스트 ID | Material
7696411 | 지상 5층 | 25FFFF | 지상 5층 | 5355816
7696419 | 지상 6층 | 25GGGG | 지상 6층 | 5356034 | KBIMS-철재 프레임, 유리
7696423 | 지상 7층 | 25HHHH | 지상 7층 | 5356252 | KBIMS-철재 프레임, 유리
7696426 | 지상 8층 | 25IIII | 지상 8층 | 5356470 | KBIMS-철재 프레임, 유리

# IfcDoor: DR121-쌍여닫이문(철재, 일반, 양개):DR121-쌍여닫이문(유리, 일반, 양개) 1500x2100mm (15)
Type - OperationType: DOUBLE_DOOR_DOUBLE_SWING; ParameterTakesPrecedence: no; Sizeable: no; Material: KBIMS-철재 프레임 (4), 유리 (3)
Type - ID 데이터(Type) - OmniClass 번호: 23.30.10.00; OmniClass 제목: Doors; 유형 마크: 113; 유형 이름: DR121-쌍여닫이문(유리, 일반, 양개) 1500x2100mm; 유형 해설: SD
Type - 기타(Type) - 카테고리: 문; 성능-도장포함 여부: no; 성능-유리포함 여부: no; KBIMS_보급정보-보급코드: bSK-191231; KBIMS_보급정보-저작자: (사)빌딩스마트협회; KBIMS_식별-버전: 1.03; KBIMS-부위코드: E333; 건설정보분류체계-부위분류: E333; 조달청표준공사코드: ALA110300000; 조달청표준공사코드-세부공종: ALA120319000A; 패밀리 이름: DR121-쌍여닫이문(철재, 일반, 양개)
Type - 시공(Type) - 기능: 내부; 벽 마무리: 호스트별
Type - 재료 및 마감재(Type) - 문패널 재료: 유리; 문프레임 재료: 유리
Type - 치수(Type) - 대략적인 높이: 0 mm; 대략적인 폭: 0 mm; 두께: 0 mm; 내부 문프레임 돌출 두께: 10 mm; 높이: 2100 mm; 문패널 두께: 15 mm; 문프레임 폭: 30 mm; 외부 문프레임 돌출 두께: 10 mm; 패널 폭: 720 mm; 폭: 1500 mm
Type - 해석 특성(Type) - 열 특성 정의 기준: 개략적 유형; 해석 시공: <없음>
Type - DR121-쌍여닫이문(철재, 일반, 양개):DR121-쌍여닫이문(유리, 일반, 양개) 1500x2100mm:7693272:1 - PanelOperation: DOUBLE_ACTING
Type - Pset_DoorCommon - IsExternal: no
OverallHeight: 2100 mm; OverallWidth: 1500 mm
Pset_DoorCommon - Reference: DR121-쌍여닫이문(유리, 일반, 양개) 1500x2100mm
Pset_QuantityTakeOff - Reference: DR121-쌍여닫이문(유리, 일반, 양개) 1500x2100mm
BaseQuantities - Height: 2100 mm; Width: 1500 mm; Area: 3.15 m2
공정 - 생성 공정: 새 구성
구속조건 - 씰 높이: 55 mm
기타 - 카테고리: 문; 유형: DR121-쌍여닫이문(유리, 일반, 양개) 1500x2100mm; 유형 ID: 7693130; 패밀리: DR121-쌍여닫이문(철재, 일반, 양개); 패밀리 및 유형: DR121-쌍여닫이문(철재, 일반, 양개): DR121-쌍여닫이문(유리, 일반, 양개) 1500x2100mm; 헤드 높이: 2155 mm
데이터 - 벽체 opening 면적: 3.15 m2
치수 - 면적: 3.8424 m2; 체적: 0.0619975 m3
Name (DR121-쌍여닫이문(철재, 일반, 양개):DR121-쌍여닫이문(유리, 일반, 양개) 1500x2100mm:...) | In | 마크 | 레벨 | 호스트 ID | Material
7693272 | 지상 2층 | 25NNN | 지상 2층 | 7690950
7693547 | 지상 2층 | 25OOO | 지상 2층 | 7690943 | KBIMS-철재 프레임, 유리
7693611 | 지상 2층 | 25PPP | 지상 2층 | 7690944 | KBIMS-철재 프레임, 유리
7693725 | 지상 2층 | 25QQQ | 지상 2층 | 7690945 | KBIMS-철재 프레임, 유리
7693777 | 지상 2층 | 25RRR | 지상 2층 | 7690946 | KBIMS-철재 프레임, 유리
7693835 | 지상 2층 | 25SSS | 지상 2층 | 7690947 | KBIMS-철재 프레임, 유리
7694685 | 지상 2층 | 25UUU | 지상 2층 | 7690948 | KBIMS-철재 프레임, 유리
7697286 | 지상 3층 | 25SSSS | 지상 3층 | 7697267 | KBIMS-철재 프레임, 유리
7697924 | 지상 3층 | 25TTTT | 지상 3층 | 7695924 | KBIMS-철재 프레임, 유리
7697999 | 지상 3층 | 25UUUU | 지상 3층 | 7695925 | KBIMS-철재 프레임, 유리
7698136 | 지상 3층 | 25VVVV | 지상 3층 | 7695959 | KBIMS-철재 프레임, 유리
7698712 | 지상 3층 | 25KKKKK | 지상 3층 | 7695960 | KBIMS-철재 프레임, 유리
7727463 | 지상 1층 | 25SSSSS | 지상 1층 | 7727460 | KBIMS-철재 프레임, 유리
7727757 | 지상 4층 | 25TTTTT | 지상 4층 | 7727752 | KBIMS-철재 프레임, 유리
7727829 | 지상 4층 | 25UUUUU | 지상 4층 | 7727754 | KBIMS-철재 프레임, 유리

# IfcDoor: DR121-쌍여닫이문(철재, 일반, 양개):DR121-쌍여닫이문(유리, 일반, 양개) 1500x2100mm (37)
Type - OperationType: DOUBLE_DOOR_DOUBLE_SWING; ParameterTakesPrecedence: no; Sizeable: no; Material: KBIMS-철재 프레임 (4), 유리 (3)
Type - ID 데이터(Type) - OmniClass 번호: 23.30.10.00; OmniClass 제목: Doors; 유형 마크: 113; 유형 이름: DR121-쌍여닫이문(유리, 일반, 양개) 1500x2100mm; 유형 해설: SD
Type - 기타(Type) - 카테고리: 문; 성능-도장포함 여부: no; 성능-유리포함 여부: no; KBIMS_보급정보-보급코드: bSK-191231; KBIMS_보급정보-저작자: (사)빌딩스마트협회; KBIMS_식별-버전: 1.03; KBIMS-부위코드: E333; 건설정보분류체계-부위분류: E333; 조달청표준공사코드: ALA110300000; 조달청표준공사코드-세부공종: ALA120319000A; 패밀리 이름: DR121-쌍여닫이문(철재, 일반, 양개)
Type - 시공(Type) - 기능: 내부; 벽 마무리: 호스트별
Type - 재료 및 마감재(Type) - 문패널 재료: 유리; 문프레임 재료: 유리
Type - 치수(Type) - 대략적인 높이: 0 mm; 대략적인 폭: 0 mm; 두께: 0 mm; 내부 문프레임 돌출 두께: 10 mm; 높이: 2100 mm; 문패널 두께: 15 mm; 문프레임 폭: 30 mm; 외부 문프레임 돌출 두께: 10 mm; 패널 폭: 720 mm; 폭: 1500 mm
Type - 해석 특성(Type) - 열 특성 정의 기준: 개략적 유형; 해석 시공: <없음>
Type - DR121-쌍여닫이문(철재, 일반, 양개):DR121-쌍여닫이문(유리, 일반, 양개) 1500x2100mm:7696564:1 - PanelOperation: DOUBLE_ACTING
Type - Pset_DoorCommon - IsExternal: no
OverallHeight: 2100 mm; OverallWidth: 1500 mm
Pset_DoorCommon - Reference: DR121-쌍여닫이문(유리, 일반, 양개) 1500x2100mm
Pset_QuantityTakeOff - Reference: DR121-쌍여닫이문(유리, 일반, 양개) 1500x2100mm
BaseQuantities - Height: 2100 mm; Width: 1500 mm; Area: 3.15 m2
공정 - 생성 공정: 새 구성
구속조건 - 씰 높이: 55 mm
기타 - 카테고리: 문; 유형: DR121-쌍여닫이문(유리, 일반, 양개) 1500x2100mm; 유형 ID: 7693130; 패밀리: DR121-쌍여닫이문(철재, 일반, 양개); 패밀리 및 유형: DR121-쌍여닫이문(철재, 일반, 양개): DR121-쌍여닫이문(유리, 일반, 양개) 1500x2100mm; 헤드 높이: 2155 mm
데이터 - 벽체 opening 면적: 3.15 m2
치수 - 면적: 3.7857 m2; 체적: 0.0603055 m3
Name (DR121-쌍여닫이문(철재, 일반, 양개):DR121-쌍여닫이문(유리, 일반, 양개) 1500x2100mm:...) | In | 마크 | 레벨 | 호스트 ID | Material
7696564 | 지상 5층 | 25MMMM | 지상 5층 | 5355823
7696567 | 지상 6층 | 25NNNN | 지상 6층 | 5356041 | KBIMS-철재 프레임, 유리
7696570 | 지상 7층 | 25OOOO | 지상 7층 | 5356259 | KBIMS-철재 프레임, 유리
7696573 | 지상 8층 | 25PPPP | 지상 8층 | 5356477 | KBIMS-철재 프레임, 유리
7696576 | 지상 9층 | 25QQQQ | 지상 9층 | 5356695 | KBIMS-철재 프레임, 유리
7698513 | 지상 4층 | 25WWWW | 지상 4층 | 5355599 | KBIMS-철재 프레임, 유리
7698514 | 지상 4층 | 25XXXX | 지상 4층 | 5397596 | KBIMS-철재 프레임, 유리
7698523 | 지상 5층 | 25YYYY | 지상 5층 | 5355817 | KBIMS-철재 프레임, 유리
7698524 | 지상 5층 | 25ZZZZ | 지상 5층 | 5397623 | KBIMS-철재 프레임, 유리
7698529 | 지상 6층 | 25AAAAA | 지상 6층 | 5356035 | KBIMS-철재 프레임, 유리
7698530 | 지상 6층 | 25BBBBB | 지상 6층 | 5397650 | KBIMS-철재 프레임, 유리
7698534 | 지상 7층 | 25CCCCC | 지상 7층 | 5356253 | KBIMS-철재 프레임, 유리
7698535 | 지상 7층 | 25DDDDD | 지상 7층 | 5397677 | KBIMS-철재 프레임, 유리
7698539 | 지상 8층 | 25EEEEE | 지상 8층 | 5356471 | KBIMS-철재 프레임, 유리
7698540 | 지상 8층 | 25FFFFF | 지상 8층 | 5397704 | KBIMS-철재 프레임, 유리
7698546 | 지상 9층 | 25GGGGG | 지상 9층 | 5356689 | KBIMS-철재 프레임, 유리
7698547 | 지상 9층 | 25HHHHH | 지상 9층 | 5393897 | KBIMS-철재 프레임, 유리
7698925 | 지상 4층 | 25LLLLL | 지상 4층 | 5355604 | KBIMS-철재 프레임, 유리
7698932 | 지상 5층 | 25MMMMM | 지상 5층 | 5355822 | KBIMS-철재 프레임, 유리
7698935 | 지상 6층 | 25NNNNN | 지상 6층 | 5356040 | KBIMS-철재 프레임, 유리
7698938 | 지상 7층 | 25OOOOO | 지상 7층 | 5356258 | KBIMS-철재 프레임, 유리
7698941 | 지상 8층 | 25PPPPP | 지상 8층 | 5356476 | KBIMS-철재 프레임, 유리
7728298 | 지상 3층 | 25VVVVV | 지상 3층 | 5354023 | KBIMS-철재 프레임, 유리
7728299 | 지상 3층 | 25WWWWW | 지상 3층 | 5354050 | KBIMS-철재 프레임, 유리
7728314 | 지상 5층 | 25XXXXX | 지상 5층 | 5355819 | KBIMS-철재 프레임, 유리
7728315 | 지상 5층 | 25YYYYY | 지상 5층 | 5355820 | KBIMS-철재 프레임, 유리
7728321 | 지상 6층 | 25ZZZZZ | 지상 6층 | 5356037 | KBIMS-철재 프레임, 유리
7728322 | 지상 6층 | 25AAAAAA | 지상 6층 | 5356038 | KBIMS-철재 프레임, 유리
7728328 | 지상 7층 | 25BBBBBB | 지상 7층 | 5356255 | KBIMS-철재 프레임, 유리
7728329 | 지상 7층 | 25CCCCCC | 지상 7층 | 5356256 | KBIMS-철재 프레임, 유리
7728335 | 지상 8층 | 25DDDDDD | 지상 8층 | 5356473 | KBIMS-철재 프레임, 유리
7728336 | 지상 8층 | 25EEEEEE | 지상 8층 | 5356474 | KBIMS-철재 프레임, 유리
7728343 | 지상 9층 | 25FFFFFF | 지상 9층 | 5356691 | KBIMS-철재 프레임, 유리
7728344 | 지상 9층 | 25GGGGGG | 지상 9층 | 5356692 | KBIMS-철재 프레임, 유리
8073327 | 지상 9층 | 25JJJJJJ | 지상 9층 | 5356694 | KBIMS-철재 프레임, 유리
8073623 | 지상 9층 | 25KKKKKK | 지상 9층 | 5909229 | KBIMS-철재 프레임, 유리
8073673 | 지상 4층 | 25MMMMMM | 지상 4층 | 5355605 | KBIMS-철재 프레임, 유리

# IfcDoor: DR121-쌍여닫이문(철재, 일반, 양개):DR121-쌍여닫이문(유리, 일반, 양개) 1500x2100mm (7)
In: 지상 10층
Type - OperationType: DOUBLE_DOOR_DOUBLE_SWING; ParameterTakesPrecedence: no; Sizeable: no; Material: KBIMS-철재 프레임 (4), 유리 (3)
Type - ID 데이터(Type) - OmniClass 번호: 23.30.10.00; OmniClass 제목: Doors; 유형 마크: 113; 유형 이름: DR121-쌍여닫이문(유리, 일반, 양개) 1500x2100mm; 유형 해설: SD
Type - 기타(Type) - 카테고리: 문; 성능-도장포함 여부: no; 성능-유리포함 여부: no; KBIMS_보급정보-보급코드: bSK-191231; KBIMS_보급정보-저작자: (사)빌딩스마트협회; KBIMS_식별-버전: 1.03; KBIMS-부위코드: E333; 건설정보분류체계-부위분류: E333; 조달청표준공사코드: ALA110300000; 조달청표준공사코드-세부공종: ALA120319000A; 패밀리 이름: DR121-쌍여닫이문(철재, 일반, 양개)
Type - 시공(Type) - 기능: 내부; 벽 마무리: 호스트별
Type - 재료 및 마감재(Type) - 문패널 재료: 유리; 문프레임 재료: 유리
Type - 치수(Type) - 대략적인 높이: 0 mm; 대략적인 폭: 0 mm; 두께: 0 mm; 내부 문프레임 돌출 두께: 10 mm; 높이: 2100 mm; 문패널 두께: 15 mm; 문프레임 폭: 30 mm; 외부 문프레임 돌출 두께: 10 mm; 패널 폭: 720 mm; 폭: 1500 mm
Type - 해석 특성(Type) - 열 특성 정의 기준: 개략적 유형; 해석 시공: <없음>
Type - DR121-쌍여닫이문(철재, 일반, 양개):DR121-쌍여닫이문(유리, 일반, 양개) 1500x2100mm:7696579:1 - PanelOperation: DOUBLE_ACTING
Type - Pset_DoorCommon - IsExternal: no
OverallHeight: 2100 mm; OverallWidth: 1500 mm
Pset_DoorCommon - Reference: DR121-쌍여닫이문(유리, 일반, 양개) 1500x2100mm
Pset_QuantityTakeOff - Reference: DR121-쌍여닫이문(유리, 일반, 양개) 1500x2100mm
BaseQuantities - Height: 2100 mm; Width: 1500 mm; Area: 3.15 m2
공정 - 생성 공정: 새 구성
구속조건 - 레벨: 지상 10층; 씰 높이: 55 mm
기타 - 카테고리: 문; 유형: DR121-쌍여닫이문(유리, 일반, 양개) 1500x2100mm; 유형 ID: 7693130; 패밀리: DR121-쌍여닫이문(철재, 일반, 양개); 패밀리 및 유형: DR121-쌍여닫이문(철재, 일반, 양개): DR121-쌍여닫이문(유리, 일반, 양개) 1500x2100mm; 헤드 높이: 2155 mm
데이터 - 벽체 opening 면적: 3.15 m2
치수 - 면적: 3.98982 m2; 체적: 0.0663967 m3
Name (DR121-쌍여닫이문(철재, 일반, 양개):DR121-쌍여닫이문(유리, 일반, 양개) 1500x2100mm:...) | 마크 | 호스트 ID | Material
7696579 | 25RRRR | 5356913
7698552 | 25IIIII | 5356907 | KBIMS-철재 프레임, 유리
7698553 | 25JJJJJ | 5356908 | KBIMS-철재 프레임, 유리
7698947 | 25RRRRR | 5356912 | KBIMS-철재 프레임, 유리
7728350 | 25HHHHHH | 5356909 | KBIMS-철재 프레임, 유리
7728351 | 25IIIIII | 5356910 | KBIMS-철재 프레임, 유리
8073629 | 25LLLLLL | 5909259 | KBIMS-철재 프레임, 유리

# IfcDoor: DR222-외미닫이 자동문(전동식) 2000X2600mm:DR222-외미닫이 자동문(전동식) 2000X2600mm, DR222-외미닫이 자동문(전동식) 2000X2600mm:DR222-외미닫이 자동문(전동식) 2000X2600mm:7363617
In: 지상 1층
Type - OperationType: SLIDING_TO_LEFT; ParameterTakesPrecedence: no; Sizeable: no; Material: KBIMS-플라스틱_검은색 (4), KBIMS-유리 (2), <Unnamed> (5)
Type - DR222-외미닫이 자동문(전동식) 2000X2600mm:DR222-외미닫이 자동문(전동식) 2000X2600mm:7363617:1 - PanelOperation: SLIDING
Type - ID 데이터 - OmniClass 번호: 23.30.10.00; OmniClass 제목: Doors; 유형 마크: 89; 유형 이름: DR222-외미닫이 자동문(전동식) 2000X2600mm; 유형 해설: SPD
Type - 그래픽 - 상부센서: yes; 터치센서: yes
Type - 기타 - 카테고리: 문; 주출입구여부: yes; KBIMS-부위코드: E333; 제작정보: AIBIM-2023; 조달청표준공사코드: ALA51; 패밀리 이름: DR222-외미닫이 자동문(전동식) 2000X2600mm
Type - 시공 - 벽 마무리: 호스트별
Type - 재료 및 마감재 - 센서 재료: KBIMS-플라스틱_검은색; 패널 재료: KBIMS-유리
Type - 치수 - A: 0 mm; B: 0 mm; 중심이동: 0 mm; 고정패널 두께_제어: 15 mm; 높이: 2600 mm; 대략적인 높이: 2600 mm; 대략적인 폭: 2090 mm; 두께: 65 mm; 문틀 간격: 20 mm; 상단작동 박스: 200 mm; 출입구 높이: 2400 mm; 출입구 폭: 1000 mm; 출입패널 두께: 20 mm; 출입패널 폭: 1045 mm; 출입프레임 높이: 100 mm; 출입프레임 두께: 30 mm; 패널 두께: 15 mm; 패널이동(문열림): 0 mm; 패널이동(문열림)_2D: 100 mm; 패널이동(문열림)_2D_제어: 100 mm; 패널 폭: 975 mm; 폭: 2090 mm; 프레임 두께: 30 mm; 프레임 폭: 45 mm
Type - 해석 특성 - 열 특성 정의 기준: 개략적 유형; 해석 시공: <없음>
Type - Pset_DoorCommon - IsExternal: no
OverallHeight: 2600 mm; OverallWidth: 2090 mm
Pset_DoorCommon - IsExternal: yes; Reference: DR222-외미닫이 자동문(전동식) 2000X2600mm
Pset_QuantityTakeOff - Reference: DR222-외미닫이 자동문(전동식) 2000X2600mm
BaseQuantities - Height: 2600 mm; Width: 2090 mm; Area: 5.434 m2
ID 데이터 - 마크: 25D
공정 - 생성 공정: 새 구성
구속조건 - 레벨: 지상 1층; 씰 높이: 0 mm
기타 - 호스트 ID: 2830676; 유형: DR222-외미닫이 자동문(전동식) 2000X2600mm; 유형 ID: 7457689; 패밀리: DR222-외미닫이 자동문(전동식) 2000X2600mm; 패밀리 및 유형: DR222-외미닫이 자동문(전동식) 2000X2600mm: DR222-외미닫이 자동문(전동식) 2000X2600mm; 헤드 높이: 2600 mm
치수 - 면적: 6.35104 m2; 체적: 0.130936 m3

# IfcDoor: DR422-회전문(전동식, 스테인리스 스틸):DR422-회전문(전동식, 스테인리스 스틸) 3000x2400mm, DR422-회전문(전동식, 스테인리스 스틸):DR422-회전문(전동식, 스테인리스 스틸) 3000x2400mm:7363509
In: 지상 1층
Type - OperationType: REVOLVING; ParameterTakesPrecedence: no; Sizeable: no; Material: <Unnamed> (8), KBIMS-스테인리스 스틸 프레임 (4), KBIMS-유리 (10)
Type - DR422-회전문(전동식, 스테인리스 스틸):DR422-회전문(전동식, 스테인리스 스틸) 3000x2400mm:7363509:1 - PanelOperation: REVOLVING
Type - ID 데이터 - OmniClass 번호: 23.30.10.00; OmniClass 제목: Doors; 모델: DR412; 설명: DR412-회전문(수동식) 3.000x2.400; 유형 마크: 69; 유형 이름: DR422-회전문(전동식, 스테인리스 스틸) 3000x2400mm; 유형 해설: RD
Type - 기타 - 카테고리: 문; 성능-도장포함 여부: no; 성능-유리포함 여부: no; KBIMS_보급정보-보급코드: bSK-191231; KBIMS_보급정보-저작자: (사)빌딩스마트협회; KBIMS_식별-버전: 1.03; KBIMS-부위코드: E333; 건설정보분류체계-부위분류: E333; 제작정보: AIBIM-2023; 조달청표준공사코드: ALA522A; 조달청표준공사코드-세부공종: LA522A; 주출입구여부: yes; 패밀리 이름: DR422-회전문(전동식, 스테인리스 스틸)
Type - 시공 - 기능: 내부; 벽 마무리: 호스트별
Type - 재료 및 마감재 - 문패널 재료: KBIMS-유리; 문프레임 재료: KBIMS-스테인리스 스틸 프레임
Type - 치수 - 두께: 0 mm; 기호선: 2355 mm; 높이: 2400 mm; 문짝 두께: 50 mm; 문프레임 폭: 130 mm; 안폭: 2900 mm; 출입구 길이: 1300 mm; 패널 높이: 2100 mm; 패널 두께: 15 mm; 패널 폭: 1410 mm; 폭: 3000 mm; 회전문 반지름: 1500 mm
Type - 해석 특성 - 열 특성 정의 기준: 개략적 유형; 해석 시공: <없음>
Type - Pset_DoorCommon - IsExternal: no
OverallHeight: 2400 mm; OverallWidth: 3000 mm
Pset_DoorCommon - Reference: DR422-회전문(전동식, 스테인리스 스틸) 3000x2400mm
Pset_QuantityTakeOff - Reference: DR422-회전문(전동식, 스테인리스 스틸) 3000x2400mm
BaseQuantities - Height: 2400 mm; Width: 3000 mm; Area: 7.2 m2
ID 데이터 - 마크: 25C
공정 - 생성 공정: 새 구성
구속조건 - 레벨: 지상 1층; 씰 높이: 0 mm
기타 - 유형: DR422-회전문(전동식, 스테인리스 스틸) 3000x2400mm; 유형 ID: 7445557; 패밀리: DR422-회전문(전동식, 스테인리스 스틸); 패밀리 및 유형: DR422-회전문(전동식, 스테인리스 스틸): DR422-회전문(전동식, 스테인리스 스틸) 3000x2400mm; 헤드 높이: 2400 mm; 호스트 ID: 2830676
치수 - 면적: 34.7941 m2; 체적: 3.05007 m3

# IfcDoor: DR872-샤프트 점검구(스테인리스 스틸):DR872-샤프트 점검구(스테인리스 스틸)_650x1600 (17)
Type - OperationType: SINGLE_SWING_LEFT; ParameterTakesPrecedence: no; Sizeable: no; Material: KBIMS-스테인리스 스틸_도금 (4)
Type - DR872-샤프트 점검구(스테인리스 스틸):DR872-샤프트 점검구(스테인리스 스틸)_650x1600:3055070:1 - PanelOperation: SWINGING
Type - ID 데이터 - OmniClass 번호: 23.30.10.00; OmniClass 제목: Doors; 유형 마크: 3; 유형 이름: DR872-샤프트 점검구(스테인리스 스틸)_650x1600; 유형 해설: SSD
Type - 기타 - 카테고리: 문; KBIMS-부위코드: E331; 제작정보: AIBIM-2023; 조달청표준공사코드: AJG3; 패밀리 이름: DR872-샤프트 점검구(스테인리스 스틸)
Type - 시공 - 기능: 내부; 벽 마무리: 호스트별
Type - 재료 및 마감재 - 문고리 재료: KBIMS-스테인리스 스틸_도금; 패널 재료: KBIMS-스테인리스 스틸_도금; 프레임 재료: KBIMS-스테인리스 스틸_도금
Type - 치수 - 구조체 간격: 0 mm; A: 0 mm; B: 0 mm; 중심이동: 0 mm; 높이: 1600 mm; 대략적인 높이: 1600 mm; 대략적인 폭: 650 mm; 두께: 150 mm; 패널 두께: 45 mm; 패널 폭: 590 mm; 폭: 650 mm; 프레임 두께: 150 mm; 프레임 폭: 60 mm; 프레임 홈: 30 mm
Type - 해석 특성 - 열 특성 정의 기준: 개략적 유형; 해석 시공: <없음>
Type - Pset_DoorCommon - IsExternal: no
OverallHeight: 1600 mm; OverallWidth: 650 mm
Pset_DoorCommon - Reference: DR872-샤프트 점검구(스테인리스 스틸)_650x1600
Pset_QuantityTakeOff - Reference: DR872-샤프트 점검구(스테인리스 스틸)_650x1600
BaseQuantities - Height: 1600 mm; Width: 650 mm; Area: 1.04 m2
공정 - 생성 공정: 새 구성
기타 - 유형: DR872-샤프트 점검구(스테인리스 스틸)_650x1600; 유형 ID: 3648337; 패밀리: DR872-샤프트 점검구(스테인리스 스틸); 패밀리 및 유형: DR872-샤프트 점검구(스테인리스 스틸): DR872-샤프트 점검구(스테인리스 스틸)_650x1600
치수 - 면적: 1.90665 m2; 체적: 0.0736435 m3
Name (DR872-샤프트 점검구(스테인리스 스틸):DR872-샤프트 점검구(스테인리스 스틸)_650x1600:...) | In | 레벨 | 씰 높이 (mm) | 헤드 높이 (mm) | 호스트 ID | Material
3055070 | 지상 3층 | 지상 3층 | 80 | 1680 | 2820443
3055071 | 지상 3층 | 지상 3층 | 80 | 1680 | 2820465 | KBIMS-스테인리스 스틸_도금
3648486 | 지상 2층 | 지상 2층 | 80 | 1680 | 2820024 | KBIMS-스테인리스 스틸_도금
3648487 | 지상 2층 | 지상 2층 | 80 | 1680 | 2820048 | KBIMS-스테인리스 스틸_도금
3648499 | 지상 4층 | 지상 4층 | 80 | 1680 | 2820693 | KBIMS-스테인리스 스틸_도금
3648500 | 지상 4층 | 지상 4층 | 80 | 1680 | 2820715 | KBIMS-스테인리스 스틸_도금
3648512 | 지상 5층 | 지상 5층 | 80 | 1680 | 2821195 | KBIMS-스테인리스 스틸_도금
3648513 | 지상 5층 | 지상 5층 | 80 | 1680 | 2821217 | KBIMS-스테인리스 스틸_도금
3648525 | 지상 6층 | 지상 6층 | 80 | 1680 | 2821455 | KBIMS-스테인리스 스틸_도금
3648526 | 지상 6층 | 지상 6층 | 80 | 1680 | 2821477 | KBIMS-스테인리스 스틸_도금
3648538 | 지상 7층 | 지상 7층 | 80 | 1680 | 2821651 | KBIMS-스테인리스 스틸_도금
3648539 | 지상 7층 | 지상 7층 | 80 | 1680 | 2821673 | KBIMS-스테인리스 스틸_도금
3648551 | 지상 8층 | 지상 8층 | 80 | 1680 | 2821997 | KBIMS-스테인리스 스틸_도금
3648552 | 지상 8층 | 지상 8층 | 80 | 1680 | 2822019 | KBIMS-스테인리스 스틸_도금
3648564 | 지상 9층 | 지상 9층 | 80 | 1680 | 2822203 | KBIMS-스테인리스 스틸_도금
3648565 | 지상 9층 | 지상 9층 | 80 | 1680 | 2822225 | KBIMS-스테인리스 스틸_도금
5918487 | 지상 1층 | 지상 1층 | 0 | 1600 | 2818536 | KBIMS-스테인리스 스틸_도금

# IfcDoor: DR872-샤프트 점검구(스테인리스 스틸):DR872-샤프트 점검구(스테인리스 스틸)_650x1600 (2)
In: 지상 10층
Type - OperationType: SINGLE_SWING_LEFT; ParameterTakesPrecedence: no; Sizeable: no; Material: KBIMS-스테인리스 스틸_도금 (4)
Type - ID 데이터 - OmniClass 번호: 23.30.10.00; OmniClass 제목: Doors; 유형 마크: 3; 유형 이름: DR872-샤프트 점검구(스테인리스 스틸)_650x1600; 유형 해설: SSD
Type - 기타 - 카테고리: 문; KBIMS-부위코드: E331; 제작정보: AIBIM-2023; 조달청표준공사코드: AJG3; 패밀리 이름: DR872-샤프트 점검구(스테인리스 스틸)
Type - 시공 - 기능: 내부; 벽 마무리: 호스트별
Type - 재료 및 마감재 - 문고리 재료: KBIMS-스테인리스 스틸_도금; 패널 재료: KBIMS-스테인리스 스틸_도금; 프레임 재료: KBIMS-스테인리스 스틸_도금
Type - 치수 - 구조체 간격: 0 mm; A: 0 mm; B: 0 mm; 중심이동: 0 mm; 높이: 1600 mm; 대략적인 높이: 1600 mm; 대략적인 폭: 650 mm; 두께: 150 mm; 패널 두께: 45 mm; 패널 폭: 590 mm; 폭: 650 mm; 프레임 두께: 150 mm; 프레임 폭: 60 mm; 프레임 홈: 30 mm
Type - 해석 특성 - 열 특성 정의 기준: 개략적 유형; 해석 시공: <없음>
Type - DR872-샤프트 점검구(스테인리스 스틸):DR872-샤프트 점검구(스테인리스 스틸)_650x1600:3648577:1 - PanelOperation: SWINGING
Type - Pset_DoorCommon - IsExternal: no
OverallHeight: 1600 mm; OverallWidth: 650 mm
Pset_DoorCommon - Reference: DR872-샤프트 점검구(스테인리스 스틸)_650x1600
Pset_QuantityTakeOff - Reference: DR872-샤프트 점검구(스테인리스 스틸)_650x1600
BaseQuantities - Height: 1600 mm; Width: 650 mm; Area: 1.04 m2
공정 - 생성 공정: 새 구성
구속조건 - 레벨: 지상 10층; 씰 높이: 80 mm
기타 - 유형: DR872-샤프트 점검구(스테인리스 스틸)_650x1600; 유형 ID: 3648337; 패밀리: DR872-샤프트 점검구(스테인리스 스틸); 패밀리 및 유형: DR872-샤프트 점검구(스테인리스 스틸): DR872-샤프트 점검구(스테인리스 스틸)_650x1600; 헤드 높이: 1680 mm
치수 - 면적: 1.90665 m2; 체적: 0.0736435 m3
Name (DR872-샤프트 점검구(스테인리스 스틸):DR872-샤프트 점검구(스테인리스 스틸)_650x1600:...) | 호스트 ID
3648577 | 2822389
3648578 | 2822411 | Material: KBIMS-스테인리스 스틸_도금

# IfcDoor: DR872-샤프트 점검구(스테인리스 스틸):DR872-샤프트 점검구(스테인리스 스틸)_650x1600, DR872-샤프트 점검구(스테인리스 스틸):DR872-샤프트 점검구(스테인리스 스틸)_650x1600:5326964
In: 지하2층
Type - OperationType: SINGLE_SWING_RIGHT; ParameterTakesPrecedence: no; Sizeable: no; Material: KBIMS-스테인리스 스틸_도금 (4)
Type - ID 데이터 - OmniClass 번호: 23.30.10.00; OmniClass 제목: Doors; 유형 마크: 3; 유형 이름: DR872-샤프트 점검구(스테인리스 스틸)_650x1600; 유형 해설: SSD
Type - 기타 - 카테고리: 문; KBIMS-부위코드: E331; 제작정보: AIBIM-2023; 조달청표준공사코드: AJG3; 패밀리 이름: DR872-샤프트 점검구(스테인리스 스틸)
Type - 시공 - 기능: 내부; 벽 마무리: 호스트별
Type - 재료 및 마감재 - 문고리 재료: KBIMS-스테인리스 스틸_도금; 패널 재료: KBIMS-스테인리스 스틸_도금; 프레임 재료: KBIMS-스테인리스 스틸_도금
Type - 치수 - 구조체 간격: 0 mm; A: 0 mm; B: 0 mm; 중심이동: 0 mm; 높이: 1600 mm; 대략적인 높이: 1600 mm; 대략적인 폭: 650 mm; 두께: 150 mm; 패널 두께: 45 mm; 패널 폭: 590 mm; 폭: 650 mm; 프레임 두께: 150 mm; 프레임 폭: 60 mm; 프레임 홈: 30 mm
Type - 해석 특성 - 열 특성 정의 기준: 개략적 유형; 해석 시공: <없음>
Type - DR872-샤프트 점검구(스테인리스 스틸):DR872-샤프트 점검구(스테인리스 스틸)_650x1600:5326964:1 - PanelOperation: SWINGING
Type - Pset_DoorCommon - IsExternal: no
OverallHeight: 1600 mm; OverallWidth: 650 mm
Pset_DoorCommon - Reference: DR872-샤프트 점검구(스테인리스 스틸)_650x1600
Pset_QuantityTakeOff - Reference: DR872-샤프트 점검구(스테인리스 스틸)_650x1600
BaseQuantities - Height: 1600 mm; Width: 650 mm; Area: 1.04 m2
공정 - 생성 공정: 새 구성
구속조건 - 레벨: PIT; 씰 높이: 160 mm
기타 - 유형: DR872-샤프트 점검구(스테인리스 스틸)_650x1600; 유형 ID: 3648337; 패밀리: DR872-샤프트 점검구(스테인리스 스틸); 패밀리 및 유형: DR872-샤프트 점검구(스테인리스 스틸): DR872-샤프트 점검구(스테인리스 스틸)_650x1600; 호스트 ID: 2809250; 헤드 높이: 1760 mm
치수 - 면적: 1.90665 m2; 체적: 0.0736435 m3

# IfcDoor: DR872-샤프트 점검구(스테인리스 스틸):DR872-샤프트 점검구(스테인리스 스틸)_650x600 (18)
Type - OperationType: SINGLE_SWING_LEFT; ParameterTakesPrecedence: no; Sizeable: no; Material: KBIMS-스테인리스 스틸_도금 (4)
Type - DR872-샤프트 점검구(스테인리스 스틸):DR872-샤프트 점검구(스테인리스 스틸)_650x600:3081304:1 - PanelOperation: SWINGING
Type - ID 데이터 - OmniClass 번호: 23.30.10.00; OmniClass 제목: Doors; 유형 마크: 4; 유형 이름: DR872-샤프트 점검구(스테인리스 스틸)_650x600; 유형 해설: SSD
Type - 기타 - 카테고리: 문; KBIMS-부위코드: E331; 제작정보: AIBIM-2023; 조달청표준공사코드: AJG3; 패밀리 이름: DR872-샤프트 점검구(스테인리스 스틸)
Type - 시공 - 기능: 내부; 벽 마무리: 호스트별
Type - 재료 및 마감재 - 문고리 재료: KBIMS-스테인리스 스틸_도금; 패널 재료: KBIMS-스테인리스 스틸_도금; 프레임 재료: KBIMS-스테인리스 스틸_도금
Type - 치수 - 구조체 간격: 0 mm; A: 0 mm; B: 0 mm; 중심이동: 0 mm; 높이: 600 mm; 대략적인 높이: 600 mm; 대략적인 폭: 650 mm; 두께: 150 mm; 패널 두께: 45 mm; 패널 폭: 590 mm; 폭: 650 mm; 프레임 두께: 150 mm; 프레임 폭: 60 mm; 프레임 홈: 30 mm
Type - 해석 특성 - 열 특성 정의 기준: 개략적 유형; 해석 시공: <없음>
Type - Pset_DoorCommon - IsExternal: no
OverallHeight: 600 mm; OverallWidth: 650 mm
Pset_DoorCommon - Reference: DR872-샤프트 점검구(스테인리스 스틸)_650x600
Pset_QuantityTakeOff - Reference: DR872-샤프트 점검구(스테인리스 스틸)_650x600
BaseQuantities - Height: 600 mm; Width: 650 mm; Area: 0.39 m2
공정 - 생성 공정: 새 구성
기타 - 패밀리: DR872-샤프트 점검구(스테인리스 스틸); 유형: DR872-샤프트 점검구(스테인리스 스틸)_650x600; 유형 ID: 3614979; 패밀리 및 유형: DR872-샤프트 점검구(스테인리스 스틸): DR872-샤프트 점검구(스테인리스 스틸)_650x600
치수 - 면적: 0.851649 m2; 체적: 0.0317935 m3
Name (DR872-샤프트 점검구(스테인리스 스틸):DR872-샤프트 점검구(스테인리스 스틸)_650x600:...) | In | 레벨 | 씰 높이 (mm) | 헤드 높이 (mm) | 호스트 ID | Material
3081304 | 지상 1층 | 지상 1층 | 600 | 1200 | 2818912
3081354 | 지상 2층 | 지상 2층 | 1200 | 1800 | 2820054 | KBIMS-스테인리스 스틸_도금
3081361 | 지상 3층 | 지상 3층 | 1200 | 1800 | 2820469 | KBIMS-스테인리스 스틸_도금
3081362 | 지상 3층 | 지상 3층 | 1200 | 1800 | 2820471 | KBIMS-스테인리스 스틸_도금
3081370 | 지상 4층 | 지상 4층 | 1200 | 1800 | 2820721 | KBIMS-스테인리스 스틸_도금
3081378 | 지상 5층 | 지상 5층 | 1200 | 1800 | 2821223 | KBIMS-스테인리스 스틸_도금
3081386 | 지상 6층 | 지상 6층 | 1200 | 1800 | 2821483 | KBIMS-스테인리스 스틸_도금
3081394 | 지상 7층 | 지상 7층 | 1200 | 1800 | 2821679 | KBIMS-스테인리스 스틸_도금
3081402 | 지상 8층 | 지상 8층 | 1200 | 1800 | 2822025 | KBIMS-스테인리스 스틸_도금
3081410 | 지상 9층 | 지상 9층 | 1200 | 1800 | 2822231 | KBIMS-스테인리스 스틸_도금
3648488 | 지상 2층 | 지상 2층 | 1200 | 1800 | 2820052 | KBIMS-스테인리스 스틸_도금
3648501 | 지상 4층 | 지상 4층 | 1200 | 1800 | 2820719 | KBIMS-스테인리스 스틸_도금
3648514 | 지상 5층 | 지상 5층 | 1200 | 1800 | 2821221 | KBIMS-스테인리스 스틸_도금
3648527 | 지상 6층 | 지상 6층 | 1200 | 1800 | 2821481 | KBIMS-스테인리스 스틸_도금
3648540 | 지상 7층 | 지상 7층 | 1200 | 1800 | 2821677 | KBIMS-스테인리스 스틸_도금
3648553 | 지상 8층 | 지상 8층 | 1200 | 1800 | 2822023 | KBIMS-스테인리스 스틸_도금
3648566 | 지상 9층 | 지상 9층 | 1200 | 1800 | 2822229 | KBIMS-스테인리스 스틸_도금
5878498 | 지상 1층 | 지상 1층 | 650 | 1250 | 2818910 | KBIMS-스테인리스 스틸_도금

# IfcDoor: DR872-샤프트 점검구(스테인리스 스틸):DR872-샤프트 점검구(스테인리스 스틸)_650x600, DR872-샤프트 점검구(스테인리스 스틸):DR872-샤프트 점검구(스테인리스 스틸)_650x600:3081418
In: 지상 10층
Type - OperationType: SINGLE_SWING_LEFT; ParameterTakesPrecedence: no; Sizeable: no; Material: KBIMS-스테인리스 스틸_도금 (4)
Type - ID 데이터 - OmniClass 번호: 23.30.10.00; OmniClass 제목: Doors; 유형 마크: 4; 유형 이름: DR872-샤프트 점검구(스테인리스 스틸)_650x600; 유형 해설: SSD
Type - 기타 - 카테고리: 문; KBIMS-부위코드: E331; 제작정보: AIBIM-2023; 조달청표준공사코드: AJG3; 패밀리 이름: DR872-샤프트 점검구(스테인리스 스틸)
Type - 시공 - 기능: 내부; 벽 마무리: 호스트별
Type - 재료 및 마감재 - 문고리 재료: KBIMS-스테인리스 스틸_도금; 패널 재료: KBIMS-스테인리스 스틸_도금; 프레임 재료: KBIMS-스테인리스 스틸_도금
Type - 치수 - 구조체 간격: 0 mm; A: 0 mm; B: 0 mm; 중심이동: 0 mm; 높이: 600 mm; 대략적인 높이: 600 mm; 대략적인 폭: 650 mm; 두께: 150 mm; 패널 두께: 45 mm; 패널 폭: 590 mm; 폭: 650 mm; 프레임 두께: 150 mm; 프레임 폭: 60 mm; 프레임 홈: 30 mm
Type - 해석 특성 - 열 특성 정의 기준: 개략적 유형; 해석 시공: <없음>
Type - DR872-샤프트 점검구(스테인리스 스틸):DR872-샤프트 점검구(스테인리스 스틸)_650x600:3081418:1 - PanelOperation: SWINGING
Type - Pset_DoorCommon - IsExternal: no
OverallHeight: 600 mm; OverallWidth: 650 mm
Pset_DoorCommon - Reference: DR872-샤프트 점검구(스테인리스 스틸)_650x600
Pset_QuantityTakeOff - Reference: DR872-샤프트 점검구(스테인리스 스틸)_650x600
BaseQuantities - Height: 600 mm; Width: 650 mm; Area: 0.39 m2
공정 - 생성 공정: 새 구성
구속조건 - 레벨: 지상 10층; 씰 높이: 1200 mm
기타 - 패밀리: DR872-샤프트 점검구(스테인리스 스틸); 유형: DR872-샤프트 점검구(스테인리스 스틸)_650x600; 유형 ID: 3614979; 패밀리 및 유형: DR872-샤프트 점검구(스테인리스 스틸): DR872-샤프트 점검구(스테인리스 스틸)_650x600; 헤드 높이: 1800 mm; 호스트 ID: 2822417
치수 - 면적: 0.851649 m2; 체적: 0.0317935 m3

# IfcDoor: DR872-샤프트 점검구(스테인리스 스틸):DR872-샤프트 점검구(스테인리스 스틸)_650x600, DR872-샤프트 점검구(스테인리스 스틸):DR872-샤프트 점검구(스테인리스 스틸)_650x600:3648579
In: 지상 10층
Type - OperationType: SINGLE_SWING_LEFT; ParameterTakesPrecedence: no; Sizeable: no; Material: KBIMS-스테인리스 스틸_도금 (4)
Type - ID 데이터 - OmniClass 번호: 23.30.10.00; OmniClass 제목: Doors; 유형 마크: 4; 유형 이름: DR872-샤프트 점검구(스테인리스 스틸)_650x600; 유형 해설: SSD
Type - 기타 - 카테고리: 문; KBIMS-부위코드: E331; 제작정보: AIBIM-2023; 조달청표준공사코드: AJG3; 패밀리 이름: DR872-샤프트 점검구(스테인리스 스틸)
Type - 시공 - 기능: 내부; 벽 마무리: 호스트별
Type - 재료 및 마감재 - 문고리 재료: KBIMS-스테인리스 스틸_도금; 패널 재료: KBIMS-스테인리스 스틸_도금; 프레임 재료: KBIMS-스테인리스 스틸_도금
Type - 치수 - 구조체 간격: 0 mm; A: 0 mm; B: 0 mm; 중심이동: 0 mm; 높이: 600 mm; 대략적인 높이: 600 mm; 대략적인 폭: 650 mm; 두께: 150 mm; 패널 두께: 45 mm; 패널 폭: 590 mm; 폭: 650 mm; 프레임 두께: 150 mm; 프레임 폭: 60 mm; 프레임 홈: 30 mm
Type - 해석 특성 - 열 특성 정의 기준: 개략적 유형; 해석 시공: <없음>
Type - DR872-샤프트 점검구(스테인리스 스틸):DR872-샤프트 점검구(스테인리스 스틸)_650x600:3648579:1 - PanelOperation: SWINGING
Type - Pset_DoorCommon - IsExternal: no
OverallHeight: 600 mm; OverallWidth: 650 mm
Pset_DoorCommon - Reference: DR872-샤프트 점검구(스테인리스 스틸)_650x600
Pset_QuantityTakeOff - Reference: DR872-샤프트 점검구(스테인리스 스틸)_650x600
BaseQuantities - Height: 600 mm; Width: 650 mm; Area: 0.39 m2
공정 - 생성 공정: 새 구성
구속조건 - 레벨: 지상 10층; 씰 높이: 1200 mm
기타 - 패밀리: DR872-샤프트 점검구(스테인리스 스틸); 유형: DR872-샤프트 점검구(스테인리스 스틸)_650x600; 유형 ID: 3614979; 패밀리 및 유형: DR872-샤프트 점검구(스테인리스 스틸): DR872-샤프트 점검구(스테인리스 스틸)_650x600; 헤드 높이: 1800 mm; 호스트 ID: 2822415
치수 - 면적: 0.851649 m2; 체적: 0.0317935 m3

# IfcDoor: EE111-엘리베이터문(문):EE111-엘리베이터문(13인승)_1100x2550 (10)
Type - OperationType: DOUBLE_DOOR_SLIDING; ParameterTakesPrecedence: no; Sizeable: no; Material: <Unnamed> (4)
Type - EE111-엘리베이터문(문):EE111-엘리베이터문(13인승)_1100x2550:3838408:1 - PanelOperation: SLIDING
Type - ID 데이터 - OmniClass 번호: 23.30.10.00; OmniClass 제목: Doors; 유형 마크: 90; 유형 이름: EE111-엘리베이터문(13인승)_1100x2550
Type - 기타 - 카테고리: 문; Frame Projection Ext.: 25 mm; Frame Projection Int.: 25 mm; Frame Width: 75 mm; KBIMS-부위코드: E66110; 조달청표준공사코드: EPA; 패밀리 이름: EE111-엘리베이터문(문)
Type - 시공 - 기능: 내부; 벽 마무리: 호스트별
Type - 치수 - A: 1350 mm; B: 1600 mm; 높이: 2550 mm; 폭: 1100 mm
Type - 해석 특성 - 열 특성 정의 기준: 개략적 유형; 해석 시공: <없음>
Type - Pset_DoorCommon - IsExternal: no
OverallHeight: 2550 mm; OverallWidth: 1100 mm
Pset_DoorCommon - Reference: EE111-엘리베이터문(13인승)_1100x2550
Pset_QuantityTakeOff - Reference: EE111-엘리베이터문(13인승)_1100x2550
BaseQuantities - Height: 2550 mm; Width: 1100 mm; Area: 2.805 m2
공정 - 생성 공정: 새 구성
기타 - 유형: EE111-엘리베이터문(13인승)_1100x2550; 유형 ID: 7620945; 패밀리: EE111-엘리베이터문(문); 패밀리 및 유형: EE111-엘리베이터문(문): EE111-엘리베이터문(13인승)_1100x2550
치수 - 면적: 4.15514 m2; 체적: 0.224818 m3
Name (EE111-엘리베이터문(문):EE111-엘리베이터문(13인승)_1100x2550:...) | In | 레벨 | 씰 높이 (mm) | 헤드 높이 (mm) | 호스트 ID | Material
3838408 | 지상 1층 | 지상 1층 | 80 | 2630 | 2818057
3839557 | 지하2층 | 지하2층 | 200 | 2750 | 2814040 | <Unnamed>
6568631 | 지상 2층 | 지상 2층 | 80 | 2630 | 2820042 | <Unnamed>
6568636 | 지상 3층 | 지상 3층 | 80 | 2630 | 2820461 | <Unnamed>
6568641 | 지상 4층 | 지상 4층 | 80 | 2630 | 2820711 | <Unnamed>
6568646 | 지상 5층 | 지상 5층 | 80 | 2630 | 2821213 | <Unnamed>
6568651 | 지상 6층 | 지상 6층 | 80 | 2630 | 2821473 | <Unnamed>
6568656 | 지상 7층 | 지상 7층 | 80 | 2630 | 2821669 | <Unnamed>
6568661 | 지상 8층 | 지상 8층 | 80 | 2630 | 2822015 | <Unnamed>
6568666 | 지상 9층 | 지상 9층 | 80 | 2630 | 2822221 | <Unnamed>

# IfcDoor: EE111-엘리베이터문(문):EE111-엘리베이터문(13인승)_1100x2550, EE111-엘리베이터문(문):EE111-엘리베이터문(13인승)_1100x2550:3839515
In: 지하1층
Type - OperationType: DOUBLE_DOOR_SLIDING; ParameterTakesPrecedence: no; Sizeable: no; Material: <Unnamed> (4)
Type - ID 데이터 - OmniClass 번호: 23.30.10.00; OmniClass 제목: Doors; 유형 마크: 90; 유형 이름: EE111-엘리베이터문(13인승)_1100x2550
Type - 기타 - 카테고리: 문; Frame Projection Ext.: 25 mm; Frame Projection Int.: 25 mm; Frame Width: 75 mm; KBIMS-부위코드: E66110; 조달청표준공사코드: EPA; 패밀리 이름: EE111-엘리베이터문(문)
Type - 시공 - 기능: 내부; 벽 마무리: 호스트별
Type - 치수 - A: 1350 mm; B: 1600 mm; 높이: 2550 mm; 폭: 1100 mm
Type - 해석 특성 - 열 특성 정의 기준: 개략적 유형; 해석 시공: <없음>
Type - EE111-엘리베이터문(문):EE111-엘리베이터문(13인승)_1100x2550:3839515:1 - PanelOperation: SLIDING
Type - Pset_DoorCommon - IsExternal: no
OverallHeight: 2550 mm; OverallWidth: 1100 mm
Pset_DoorCommon - Reference: EE111-엘리베이터문(13인승)_1100x2550
Pset_QuantityTakeOff - Reference: EE111-엘리베이터문(13인승)_1100x2550
BaseQuantities - Height: 2550 mm; Width: 1100 mm; Area: 2.805 m2
공정 - 생성 공정: 새 구성
구속조건 - 레벨: 지하1층; 씰 높이: 200 mm
기타 - 유형: EE111-엘리베이터문(13인승)_1100x2550; 유형 ID: 7620945; 패밀리: EE111-엘리베이터문(문); 패밀리 및 유형: EE111-엘리베이터문(문): EE111-엘리베이터문(13인승)_1100x2550; 헤드 높이: 2750 mm; 호스트 ID: 2816481
치수 - 면적: 4.15514 m2; 체적: 0.224818 m3

# IfcDoor: EE111-엘리베이터문(문):EE111-엘리베이터문(13인승)_1100x2550, EE111-엘리베이터문(문):EE111-엘리베이터문(13인승)_1100x2550:6568671
In: 지상 10층
Type - OperationType: DOUBLE_DOOR_SLIDING; ParameterTakesPrecedence: no; Sizeable: no; Material: <Unnamed> (4)
Type - ID 데이터 - OmniClass 번호: 23.30.10.00; OmniClass 제목: Doors; 유형 마크: 90; 유형 이름: EE111-엘리베이터문(13인승)_1100x2550
Type - 기타 - 카테고리: 문; Frame Projection Ext.: 25 mm; Frame Projection Int.: 25 mm; Frame Width: 75 mm; KBIMS-부위코드: E66110; 조달청표준공사코드: EPA; 패밀리 이름: EE111-엘리베이터문(문)
Type - 시공 - 기능: 내부; 벽 마무리: 호스트별
Type - 치수 - A: 1350 mm; B: 1600 mm; 높이: 2550 mm; 폭: 1100 mm
Type - 해석 특성 - 열 특성 정의 기준: 개략적 유형; 해석 시공: <없음>
Type - EE111-엘리베이터문(문):EE111-엘리베이터문(13인승)_1100x2550:6568671:1 - PanelOperation: SLIDING
Type - Pset_DoorCommon - IsExternal: no
OverallHeight: 2550 mm; OverallWidth: 1100 mm
Pset_DoorCommon - Reference: EE111-엘리베이터문(13인승)_1100x2550
Pset_QuantityTakeOff - Reference: EE111-엘리베이터문(13인승)_1100x2550
BaseQuantities - Height: 2550 mm; Width: 1100 mm; Area: 2.805 m2
공정 - 생성 공정: 새 구성
구속조건 - 레벨: 지상 10층; 씰 높이: 80 mm
기타 - 유형: EE111-엘리베이터문(13인승)_1100x2550; 유형 ID: 7620945; 패밀리: EE111-엘리베이터문(문); 패밀리 및 유형: EE111-엘리베이터문(문): EE111-엘리베이터문(13인승)_1100x2550; 헤드 높이: 2630 mm; 호스트 ID: 2822407
치수 - 면적: 4.34322 m2; 체적: 0.244746 m3

# IfcDoor: EE111-엘리베이터문(문):EE111-엘리베이터문(20인승)_1100x2550 (20)
Type - OperationType: DOUBLE_DOOR_SLIDING; ParameterTakesPrecedence: no; Sizeable: no; Material: <Unnamed> (4)
Type - EE111-엘리베이터문(문):EE111-엘리베이터문(20인승)_1100x2550:3838630:1 - PanelOperation: SLIDING
Type - ID 데이터 - OmniClass 번호: 23.30.10.00; OmniClass 제목: Doors; 유형 마크: 92; 유형 이름: EE111-엘리베이터문(20인승)_1100x2550
Type - 기타 - 카테고리: 문; Frame Projection Ext.: 25 mm; Frame Projection Int.: 25 mm; Frame Width: 75 mm; KBIMS-부위코드: E66110; 조달청표준공사코드: EPA; 패밀리 이름: EE111-엘리베이터문(문)
Type - 시공 - 기능: 내부; 벽 마무리: 호스트별
Type - 치수 - A: 1900 mm; B: 1950 mm; 높이: 2550 mm; 폭: 1100 mm
Type - 해석 특성 - 열 특성 정의 기준: 개략적 유형; 해석 시공: <없음>
Type - Pset_DoorCommon - IsExternal: no
OverallHeight: 2550 mm; OverallWidth: 1100 mm
Pset_DoorCommon - Reference: EE111-엘리베이터문(20인승)_1100x2550
Pset_QuantityTakeOff - Reference: EE111-엘리베이터문(20인승)_1100x2550
BaseQuantities - Height: 2550 mm; Width: 1100 mm; Area: 2.805 m2
공정 - 생성 공정: 새 구성
구속조건 - 씰 높이: 80 mm
기타 - 패밀리: EE111-엘리베이터문(문); 유형: EE111-엘리베이터문(20인승)_1100x2550; 유형 ID: 7620949; 패밀리 및 유형: EE111-엘리베이터문(문): EE111-엘리베이터문(20인승)_1100x2550; 헤드 높이: 2630 mm
치수 - 면적: 4.15514 m2; 체적: 0.224818 m3
Name (EE111-엘리베이터문(문):EE111-엘리베이터문(20인승)_1100x2550:...) | In | 레벨 | 호스트 ID | Material
3838630 | 지상 1층 | 지상 1층 | 2818041
3838757 | 지상 1층 | 지상 1층 | 2818041 | <Unnamed>
3839171 | 지상 2층 | 지상 2층 | 2820026 | <Unnamed>
3839172 | 지상 2층 | 지상 2층 | 2820026 | <Unnamed>
3839180 | 지상 3층 | 지상 3층 | 2820445 | <Unnamed>
3839181 | 지상 3층 | 지상 3층 | 2820445 | <Unnamed>
3839222 | 지상 4층 | 지상 4층 | 2820695 | <Unnamed>
3839223 | 지상 4층 | 지상 4층 | 2820695 | <Unnamed>
3839264 | 지상 5층 | 지상 5층 | 2821197 | <Unnamed>
3839265 | 지상 5층 | 지상 5층 | 2821197 | <Unnamed>
3839306 | 지상 6층 | 지상 6층 | 2821457 | <Unnamed>
3839307 | 지상 6층 | 지상 6층 | 2821457 | <Unnamed>
3839348 | 지상 7층 | 지상 7층 | 2821653 | <Unnamed>
3839349 | 지상 7층 | 지상 7층 | 2821653 | <Unnamed>
3839390 | 지상 8층 | 지상 8층 | 2821999 | <Unnamed>
3839391 | 지상 8층 | 지상 8층 | 2821999 | <Unnamed>
3839432 | 지상 9층 | 지상 9층 | 2822205 | <Unnamed>
3839433 | 지상 9층 | 지상 9층 | 2822205 | <Unnamed>
3839558 | 지하2층 | 지하2층 | 5998070 | <Unnamed>
3839559 | 지하2층 | 지하2층 | 5998070 | <Unnamed>

# IfcDoor: EE111-엘리베이터문(문):EE111-엘리베이터문(20인승)_1100x2550 (2)
In: 지상 10층
Type - OperationType: DOUBLE_DOOR_SLIDING; ParameterTakesPrecedence: no; Sizeable: no; Material: <Unnamed> (4)
Type - ID 데이터 - OmniClass 번호: 23.30.10.00; OmniClass 제목: Doors; 유형 마크: 92; 유형 이름: EE111-엘리베이터문(20인승)_1100x2550
Type - 기타 - 카테고리: 문; Frame Projection Ext.: 25 mm; Frame Projection Int.: 25 mm; Frame Width: 75 mm; KBIMS-부위코드: E66110; 조달청표준공사코드: EPA; 패밀리 이름: EE111-엘리베이터문(문)
Type - 시공 - 기능: 내부; 벽 마무리: 호스트별
Type - 치수 - A: 1900 mm; B: 1950 mm; 높이: 2550 mm; 폭: 1100 mm
Type - 해석 특성 - 열 특성 정의 기준: 개략적 유형; 해석 시공: <없음>
Type - EE111-엘리베이터문(문):EE111-엘리베이터문(20인승)_1100x2550:3839474:1 - PanelOperation: SLIDING
Type - Pset_DoorCommon - IsExternal: no
OverallHeight: 2550 mm; OverallWidth: 1100 mm
Pset_DoorCommon - Reference: EE111-엘리베이터문(20인승)_1100x2550
Pset_QuantityTakeOff - Reference: EE111-엘리베이터문(20인승)_1100x2550
BaseQuantities - Height: 2550 mm; Width: 1100 mm; Area: 2.805 m2
공정 - 생성 공정: 새 구성
구속조건 - 레벨: 지상 10층; 씰 높이: 80 mm
기타 - 패밀리: EE111-엘리베이터문(문); 유형: EE111-엘리베이터문(20인승)_1100x2550; 유형 ID: 7620949; 패밀리 및 유형: EE111-엘리베이터문(문): EE111-엘리베이터문(20인승)_1100x2550; 헤드 높이: 2630 mm; 호스트 ID: 2822391
치수 - 면적: 4.34322 m2; 체적: 0.244746 m3
Name (EE111-엘리베이터문(문):EE111-엘리베이터문(20인승)_1100x2550:...)
3839474
3839475 | Material: <Unnamed>

# IfcDoor: EE111-엘리베이터문(문):EE111-엘리베이터문(20인승)_1100x2550 (2)
In: 지하1층
Type - OperationType: DOUBLE_DOOR_SLIDING; ParameterTakesPrecedence: no; Sizeable: no; Material: <Unnamed> (4)
Type - ID 데이터 - OmniClass 번호: 23.30.10.00; OmniClass 제목: Doors; 유형 마크: 92; 유형 이름: EE111-엘리베이터문(20인승)_1100x2550
Type - 기타 - 카테고리: 문; Frame Projection Ext.: 25 mm; Frame Projection Int.: 25 mm; Frame Width: 75 mm; KBIMS-부위코드: E66110; 조달청표준공사코드: EPA; 패밀리 이름: EE111-엘리베이터문(문)
Type - 시공 - 기능: 내부; 벽 마무리: 호스트별
Type - 치수 - A: 1900 mm; B: 1950 mm; 높이: 2550 mm; 폭: 1100 mm
Type - 해석 특성 - 열 특성 정의 기준: 개략적 유형; 해석 시공: <없음>
Type - EE111-엘리베이터문(문):EE111-엘리베이터문(20인승)_1100x2550:3839516:1 - PanelOperation: SLIDING
Type - Pset_DoorCommon - IsExternal: no
OverallHeight: 2550 mm; OverallWidth: 1100 mm
Pset_DoorCommon - Reference: EE111-엘리베이터문(20인승)_1100x2550
Pset_QuantityTakeOff - Reference: EE111-엘리베이터문(20인승)_1100x2550
BaseQuantities - Height: 2550 mm; Width: 1100 mm; Area: 2.805 m2
공정 - 생성 공정: 새 구성
구속조건 - 레벨: 지하1층; 씰 높이: 200 mm
기타 - 패밀리: EE111-엘리베이터문(문); 유형: EE111-엘리베이터문(20인승)_1100x2550; 유형 ID: 7620949; 패밀리 및 유형: EE111-엘리베이터문(문): EE111-엘리베이터문(20인승)_1100x2550; 헤드 높이: 2750 mm; 호스트 ID: 2816465
치수 - 면적: 4.15514 m2; 체적: 0.224818 m3
Name (EE111-엘리베이터문(문):EE111-엘리베이터문(20인승)_1100x2550:...)
3839516
3839517 | Material: <Unnamed>

# IfcDoor: SE251-장애인전용 표시:SE251-장애인전용 표시 (18)
Type - ParameterTakesPrecedence: no; Sizeable: no; Material: KBIMS-노면용 페인트_진하늘색 (2)
Type - ID 데이터 - 유형 이름: SE251-장애인전용 표시
Type - 구속조건 - 기본 높이: 0 mm
Type - 기타 - 카테고리: 가구; KBIMS-부위코드: E77; 제작정보: AIBIM-2023; 조달청표준공사코드: CLH2603; 패밀리 이름: SE251-장애인전용 표시
Type - 치수 - 높이: 0 mm
Type - Pset_DoorCommon - IsExternal: no
OverallHeight: 1.5875 mm; OverallWidth: 572.371 mm
Pset_DoorCommon - Reference: SE251-장애인전용 표시
Pset_QuantityTakeOff - Reference: SE251-장애인전용 표시
BaseQuantities - Area: 0.0656659 m2
공정 - 생성 공정: 새 구성
구속조건 - 가까운 요소로 이동: no; 레벨로부터의 높이: 0 mm; 호스트에서의 간격띄우기: 0 mm
기타 - 유형: SE251-장애인전용 표시; 유형 ID: 3121236; 패밀리: SE251-장애인전용 표시; 패밀리 및 유형: SE251-장애인전용 표시: SE251-장애인전용 표시
치수 - 면적: 0.117875 m2; 체적: 0.000182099 m3
Name (SE251-장애인전용 표시:SE251-장애인전용 표시:...) | In | 레벨 | 호스트 | Material
3145946 | 지상 2층 | 지상 2층 | 레벨 : 지상 2층
3145947 | 지상 2층 | 지상 2층 | 레벨 : 지상 2층 | KBIMS-노면용 페인트_진하늘색
3146259 | 지상 3층 | 지상 3층 | 레벨 : 지상 3층 | KBIMS-노면용 페인트_진하늘색
3146260 | 지상 3층 | 지상 3층 | 레벨 : 지상 3층 | KBIMS-노면용 페인트_진하늘색
3146318 | 지상 4층 | 지상 4층 | 레벨 : 지상 4층 | KBIMS-노면용 페인트_진하늘색
3146319 | 지상 4층 | 지상 4층 | 레벨 : 지상 4층 | KBIMS-노면용 페인트_진하늘색
3146377 | 지상 5층 | 지상 5층 | 레벨 : 지상 5층 | KBIMS-노면용 페인트_진하늘색
3146378 | 지상 5층 | 지상 5층 | 레벨 : 지상 5층 | KBIMS-노면용 페인트_진하늘색
3146436 | 지상 6층 | 지상 6층 | 레벨 : 지상 6층 | KBIMS-노면용 페인트_진하늘색
3146437 | 지상 6층 | 지상 6층 | 레벨 : 지상 6층 | KBIMS-노면용 페인트_진하늘색
3146495 | 지상 7층 | 지상 7층 | 레벨 : 지상 7층 | KBIMS-노면용 페인트_진하늘색
3146496 | 지상 7층 | 지상 7층 | 레벨 : 지상 7층 | KBIMS-노면용 페인트_진하늘색
3146554 | 지상 8층 | 지상 8층 | 레벨 : 지상 8층 | KBIMS-노면용 페인트_진하늘색
3146555 | 지상 8층 | 지상 8층 | 레벨 : 지상 8층 | KBIMS-노면용 페인트_진하늘색
3146613 | 지상 9층 | 지상 9층 | 레벨 : 지상 9층 | KBIMS-노면용 페인트_진하늘색
3146614 | 지상 9층 | 지상 9층 | 레벨 : 지상 9층 | KBIMS-노면용 페인트_진하늘색
3146672 | 지상 10층 | 지상 10층 | 레벨 : 지상 10층 | KBIMS-노면용 페인트_진하늘색
3146673 | 지상 10층 | 지상 10층 | 레벨 : 지상 10층 | KBIMS-노면용 페인트_진하늘색

# IfcFlowFitting: M_래더 수평 구부림:표준, M_래더 수평 구부림:표준:7855333
In: 지상 1층
Type - Material: <Unnamed> (7)
Type - ID 데이터 - OmniClass 번호: 23.80.30.17.17; OmniClass 제목: Cable Trays and Horizontal Racks; 유형 이름: 표준
Type - 구속조건 - 기본 높이: 0 mm
Type - 기타 - 카테고리: 케이블 트레이 부속류; 패밀리 이름: M_래더 수평 구부림
Pset_DistributionFlowElementCommon - Reference: 표준; sets with these values: 2
공정 - 생성 공정: 새 구성
구속조건 - 레벨: 지상 1층; 레벨로부터의 높이: 3780 mm
그래픽 - 주석 축척 사용: no
기타 - 가시성 1: yes; 가시성 2: yes; 각도 1: 45 deg; 각도 2: 180 deg; 각도 3: 22.5 deg; 각도 4: 67.5 deg; 간격띄우기: 50 mm; 구부림 또는 부속품: 부속품; 구부림 반지름 레이블: 600 mm; 길이 1: 600 mm; 길이 2: 325.4 mm; 길이 3: 549.2 mm; 유형: 표준; 유형 ID: 7855792; 패밀리: M_래더 수평 구부림; 패밀리 및 유형: M_래더 수평 구부림: 표준; 호 길이: 942.48 mm
치수 - 각도: 90 deg; 가로장 공간: 228.6 mm; 가로장 높이: 25.4 mm; 가로장 폭: 25.4 mm; 구부림 반지름: 300 mm; 두께: 25.4 mm; 체적: 0.0661484 m3; 크기: 600 mmx100 mmø-600 mmx100 mmø; 트레이 길이: 80 mm; 트레이 높이: 100 mm; 트레이 폭: 600 mm
Group: 모델 그룹:MEP 2:7855242

# IfcFlowFitting: M_래더 수평 티:300mm 반지름 (2)
In: 지상 1층
Type - Material: <Unnamed> (8)
Type - ID 데이터 - OmniClass 번호: 23.80.30.17.17; OmniClass 제목: Cable Trays and Horizontal Racks; 유형 이름: 300mm 반지름
Type - 구속조건 - 기본 높이: 0 mm
Type - 기타 - 카테고리: 케이블 트레이 부속류; 패밀리 이름: M_래더 수평 티
Type - 치수 - 반지름: 300 mm
Pset_DistributionFlowElementCommon - Reference: 300mm 반지름; sets with these values: 2
공정 - 생성 공정: 새 구성
구속조건 - 레벨: 지상 1층; 레벨로부터의 높이: 3780 mm
그래픽 - 주석 축척 사용: no
기타 - 가시성 1: yes; 가시성 2: no; 가시성 3: yes; 가시성 4: yes; 길이 1: 274.08 mm; 길이 2: 325.92 mm; 길이 3: 1200 mm; 반지름 레이블: 300 mm; 반지름 레이블 1: 325.4 mm; 유형: 300mm 반지름; 유형 ID: 7855794; 패밀리: M_래더 수평 티; 패밀리 및 유형: M_래더 수평 티: 300mm 반지름
치수 - 가로장 공간: 228.6 mm; 가로장 높이: 25.4 mm; 가로장 폭: 25.4 mm; 두께: 25.4 mm; 크기: 600 mmx100 mmø-600 mmx100 mmø-600 mmx100 mmø; 트레이 높이: 100 mm; 트레이 폭 1: 600 mm; 트레이 폭 3: 600 mm
Group: 모델 그룹:MEP 2:7855242
Name (M_래더 수평 티:300mm 반지름:...) | 체적 (m3) | 트레이 길이 (mm)
7855335 | 0.108263 | 80
7855337 | 0.102863 | 50

# IfcFlowFitting: M_원형 견적:RA (9)
In: 지상 1층
Type - Material: <Unnamed>
Type - ID 데이터 - OmniClass 번호: 23.75.70.14; OmniClass 제목: Air Ductwork; 유형 이름: RA
Type - 구속조건 - 기본 높이: 0 mm
Type - 기타 - 카테고리: 덕트 부속; 패밀리 이름: M_원형 견적
Pset_DistributionFlowElementCommon - Reference: RA; sets with these values: 2
공정 - 생성 공정: 새 구성
구속조건 - 레벨: 지상 1층; 레벨로부터의 높이: 4180 mm
그래픽 - 주석 축척 사용: no
기계 - 시스템 유형: Return Air; 시스템 분류: 순환 공기
기타 - 유형: RA; 패밀리: M_원형 견적; 유형 ID: 7855782; 패밀리 및 유형: M_원형 견적: RA
단열재 - 단열재 두께: 0 mm; 전체 크기: 150 mm-150 mm
라이닝 - 라이닝 두께: 0 mm; 사용 가능한 크기: 150 mm-150 mm
치수 - 덕트 반지름: 75 mm; 덕트 지름: 150 mm; 분지 고정 길이: 101.6; 크기: 150 mm-150 mm
Name (M_원형 견적:RA:...) | 시스템 이름 | 분지 길이 | 분지 길이 투영 | 체적 (m3) | Group
7855299 | 기계 Return Air 2 | 101.6 | 6.096 | 0.00190305 | 모델 그룹:MEP 2:7855242; 기계 Return Air 2
7855302 | 기계 Return Air 2 | 101.6 | 6.096 | 0.00190305 | 모델 그룹:MEP 2:7855242; 기계 Return Air 2
7855305 | 기계 Return Air 2 | 101.6 | 6.096 | 0.00190305 | 모델 그룹:MEP 2:7855242; 기계 Return Air 2
7855308 | 기계 Return Air 3 | 101.622 | 6.11766 | 0.00190382 | 모델 그룹:MEP 2:7855242; 기계 Return Air 3
7855311 | 기계 Return Air 3 | 101.6 | 6.096 | 0.00190305 | 모델 그룹:MEP 2:7855242; 기계 Return Air 3
7855320 | 기계 Return Air 7 | 101.6 | 39.9522 | 0.00250131 | 모델 그룹:MEP 2:7855242; 기계 Return Air 7
7855323 | 기계 Return Air 7 | 101.6 | 39.9522 | 0.00250131 | 모델 그룹:MEP 2:7855242; 기계 Return Air 7
7855326 | 기계 Return Air 8 | 101.6 | 39.9522 | 0.00250131 | 모델 그룹:MEP 2:7855242; 기계 Return Air 8
7855329 | 기계 Return Air 8 | 101.6 | 39.9522 | 0.00250131 | 모델 그룹:MEP 2:7855242; 기계 Return Air 8

# IfcFlowFitting: M_원형 견적:SA (5)
In: 지상 1층
Type - Material: <Unnamed>
Type - ID 데이터 - OmniClass 번호: 23.75.70.14; OmniClass 제목: Air Ductwork; 유형 이름: SA
Type - 구속조건 - 기본 높이: 0 mm
Type - 기타 - 카테고리: 덕트 부속; 패밀리 이름: M_원형 견적
Pset_DistributionFlowElementCommon - Reference: SA; sets with these values: 2
공정 - 생성 공정: 새 구성
구속조건 - 레벨: 지상 1층; 레벨로부터의 높이: 4180 mm
그래픽 - 주석 축척 사용: no
기계 - 시스템 유형: Supply Air; 시스템 분류: 공급 공기
기타 - 유형: SA; 유형 ID: 7855778; 패밀리: M_원형 견적; 패밀리 및 유형: M_원형 견적: SA
단열재 - 단열재 두께: 0 mm; 전체 크기: 150 mm-150 mm
라이닝 - 라이닝 두께: 0 mm; 사용 가능한 크기: 150 mm-150 mm
치수 - 덕트 반지름: 75 mm; 덕트 지름: 150 mm; 분지 고정 길이: 101.6; 크기: 150 mm-150 mm
Name (M_원형 견적:SA:...) | 시스템 이름 | 분지 길이 | 분지 길이 투영 | 체적 (m3) | Group
7855290 | 기계 Supply Air 2 | 101.6 | 6.096 | 0.00190305 | 모델 그룹:MEP 2:7855242; 기계 Supply Air 2
7855293 | 기계 Supply Air 2 | 101.6 | 6.096 | 0.00190305 | 모델 그룹:MEP 2:7855242; 기계 Supply Air 2
7855296 | 기계 Supply Air 2 | 101.6 | 6.096 | 0.00190305 | 모델 그룹:MEP 2:7855242; 기계 Supply Air 2
7855314 | 기계 Supply Air 4 | 101.652 | 6.14798 | 0.00190489 | 모델 그룹:MEP 2:7855242; 기계 Supply Air 4
7855317 | 기계 Supply Air 4 | 101.6 | 6.096 | 0.00190305 | 모델 그룹:MEP 2:7855242; 기계 Supply Air 4

# IfcFlowFitting: M_원형 끝마감:RA (2)
In: 지상 1층
Type - Material: <Unnamed>
Type - ID 데이터 - OmniClass 번호: 23.75.70.14; OmniClass 제목: Air Ductwork; 유형 이름: RA
Type - 구속조건 - 기본 높이: 0 mm
Type - 기타 - 카테고리: 덕트 부속; 패밀리 이름: M_원형 끝마감
Type - 치수 - 덕트 길이: 25 mm
Pset_DistributionFlowElementCommon - Reference: RA; sets with these values: 2
공정 - 생성 공정: 새 구성
구속조건 - 레벨: 지상 1층; 레벨로부터의 높이: 4180 mm
그래픽 - 주석 축척 사용: no
기계 - 시스템 유형: Return Air; 시스템 분류: 순환 공기
기계 - 흐름 - 압력 강하: 0 Pa
기타 - 유형: RA; 유형 ID: 7855786; 패밀리: M_원형 끝마감; 패밀리 및 유형: M_원형 끝마감: RA
단열재 - 단열재 두께: 0 mm; 전체 크기: 200 mm
라이닝 - 라이닝 두께: 0 mm; 사용 가능한 크기: 200 mm
치수 - 덕트 반지름: 100 mm; 체적: 0.000785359 m3; 크기: 200 mm
Name (M_원형 끝마감:RA:...) | 시스템 이름 | Group
7855264 | 기계 Return Air 7 | 모델 그룹:MEP 2:7855242; 기계 Return Air 7
7855265 | 기계 Return Air 8 | 모델 그룹:MEP 2:7855242; 기계 Return Air 8

# IfcFlowFitting: M_원형 엘보:RA, M_원형 엘보:RA:7855269
In: 지상 1층
Type - Material: <Unnamed> (2)
Type - ID 데이터 - OmniClass 번호: 23.75.70.14; OmniClass 제목: Air Ductwork; 유형 이름: RA
Type - 구속조건 - 기본 높이: 0 mm
Type - 기타 - 카테고리: 덕트 부속; 패밀리 이름: M_원형 엘보
Pset_DistributionFlowElementCommon - Reference: RA; sets with these values: 2
공정 - 생성 공정: 새 구성
구속조건 - 레벨: 지상 1층; 레벨로부터의 높이: 4180 mm
그래픽 - 주석 축척 사용: no
기계 - 시스템 유형: Return Air; 시스템 분류: 순환 공기; 시스템 이름: 기계 Return Air 8
기타 - 유형: RA; 유형 ID: 7855790; 패밀리: M_원형 엘보; 패밀리 및 유형: M_원형 엘보: RA
단열재 - 단열재 두께: 0 mm; 전체 크기: 200 mm-200 mm
라이닝 - 라이닝 두께: 0 mm; 사용 가능한 크기: 200 mm-200 mm
치수 - 각도: 90 deg; 길이1: 200 mm; 덕트 반지름: 100 mm; 반지름 승수: 1; 중심 반지름: 200 mm; 체적: 0.00986929 m3; 크기: 200 mm-200 mm
Group: 모델 그룹:MEP 2:7855242; 기계 Return Air 8

# IfcFlowFitting: M_직사각형 끝마감:RA (2)
In: 지상 1층
Type - Material: <Unnamed>
Type - ID 데이터 - OmniClass 번호: 23.75.70.14; OmniClass 제목: Air Ductwork; 유형 이름: RA
Type - 구속조건 - 기본 높이: 0 mm
Type - 기타 - 카테고리: 덕트 부속; 패밀리 이름: M_직사각형 끝마감
Type - 치수 - 덕트 길이: 25 mm
Pset_DistributionFlowElementCommon - Reference: RA; sets with these values: 2
공정 - 생성 공정: 새 구성
구속조건 - 레벨: 지상 1층; 레벨로부터의 높이: 4180 mm
그래픽 - 주석 축척 사용: no
기계 - 시스템 유형: Return Air; 시스템 분류: 순환 공기
기계 - 흐름 - 압력 강하: 0 Pa
기타 - 유형: RA; 유형 ID: 7855772; 패밀리: M_직사각형 끝마감; 패밀리 및 유형: M_직사각형 끝마감: RA
단열재 - 단열재 두께: 0 mm
라이닝 - 라이닝 두께: 0 mm
Name (M_직사각형 끝마감:RA:...) | 시스템 이름 | 전체 크기 = 사용 가능한 크기 = 크기 | 덕트 높이 (mm) | 덕트 폭 (mm) | 체적 (m3) | Group
7855254 | 기계 Return Air 3 | 250 mmx200 mm | 200 | 250 | 0.00125 | 모델 그룹:MEP 2:7855242; 기계 Return Air 3
7855255 | 기계 Return Air 2 | 300 mmx250 mm | 250 | 300 | 0.001875 | 모델 그룹:MEP 2:7855242; 기계 Return Air 2

# IfcFlowFitting: M_직사각형 끝마감:SA (3)
In: 지상 1층
Type - Material: <Unnamed>
Type - ID 데이터 - OmniClass 번호: 23.75.70.14; OmniClass 제목: Air Ductwork; 유형 이름: SA
Type - 구속조건 - 기본 높이: 0 mm
Type - 기타 - 카테고리: 덕트 부속; 패밀리 이름: M_직사각형 끝마감
Type - 치수 - 덕트 길이: 25 mm
Pset_DistributionFlowElementCommon - Reference: SA; sets with these values: 2
공정 - 생성 공정: 새 구성
구속조건 - 레벨: 지상 1층
그래픽 - 주석 축척 사용: no
기계 - 흐름 - 압력 강하: 0 Pa
기타 - 유형: SA; 패밀리: M_직사각형 끝마감; 유형 ID: 7855762; 패밀리 및 유형: M_직사각형 끝마감: SA
단열재 - 단열재 두께: 0 mm
라이닝 - 라이닝 두께: 0 mm
Name (M_직사각형 끝마감:SA:...) | 레벨로부터의 높이 (mm) | 시스템 유형 | 시스템 분류 | 시스템 이름 | 전체 크기 = 사용 가능한 크기 = 크기 | 덕트 높이 (mm) | 덕트 폭 (mm) | 체적 (m3) | Group
7855256 | 4180 | Supply Air | 공급 공기 | 기계 Supply Air 2 | 300 mmx250 mm | 250 | 300 | 0.001875 | 모델 그룹:MEP 2:7855242; 기계 Supply Air 2
7855268 | 4180 | Return Air | 순환 공기 | 기계 Return Air 11 | 250 mmx200 mm | 200 | 250 | 0.00125 | 모델 그룹:MEP 2:7855242; 기계 Supply Air 4
7855330 | 4105 | Supply Air | 공급 공기 | 기계 Supply Air 1 | 400 mmx250 mm | 250 | 400 | 0.0025 | 모델 그룹:MEP 2:7855242; 기계 Supply Air 1

# IfcFlowFitting: M_직사각형 변환 - 각도:RA (2)
In: 지상 1층
Type - Material: <Unnamed>
Type - ID 데이터 - OmniClass 번호: 23.75.70.14; OmniClass 제목: Air Ductwork; 유형 이름: RA
Type - 구속조건 - 기본 높이: 0 mm
Type - 기타 - 카테고리: 덕트 부속; 패밀리 이름: M_직사각형 변환 - 각도
Pset_DistributionFlowElementCommon - Reference: RA; sets with these values: 2
공정 - 생성 공정: 새 구성
구속조건 - 레벨: 지상 1층; 각도: 60 deg; 레벨로부터의 높이: 4180 mm
그래픽 - 주석 축척 사용: no
기계 - 시스템 유형: Return Air; 시스템 분류: 순환 공기
기타 - 유형: RA; 델타 1: 0 mm; 델타 2: 0 mm; 유형 ID: 7855767; 패밀리: M_직사각형 변환 - 각도; 패밀리 및 유형: M_직사각형 변환 - 각도: RA
단열재 - 단열재 두께: 0 mm
라이닝 - 라이닝 두께: 0 mm
치수 - 계산한 길이: 86.6025 mm; 덕트 길이: 86.6025 mm; 최대 델타: 86.6025 mm
Name (M_직사각형 변환 - 각도:RA:...) | 시스템 이름 | 길이 1 (mm) | 길이 2 (mm) | 번호1 = 번호2 | 번호3 | 번호4 | 번호5 = 번호6 | 번호7 | 번호8 | 전체 크기 = 사용 가능한 크기 = 크기 | 높이 간격띄우기 = 절반 높이 1 (mm) | 높이 델타 (mm) | 덕트 높이 1 (mm) | 덕트 높이 2 (mm) | 덕트 폭 1 (mm) | 덕트 폭 2 (mm) | 면적 (m2) | 절반 높이 2 (mm) | 절반 폭 1 (mm) = 폭 간격띄우기 | 절반 폭 2 (mm) | 체적 (m3) | 폭 델타 (mm) | Group
7855270 | 기계 Return Air 6 | 86.6025 | 43.3013 | 1 | 0.333333 | 0.57735 | 2 | 1.33333 | 1.1547 | 450 mmx350 mm-400 mmx250 mm | 175 | 100 | 350 | 250 | 450 | 400 | 0.117549 | 125 | 225 | 200 | 0.0110779 | 50 | 모델 그룹:MEP 2:7855242; 기계 Return Air 6
7855271 | 기계 Return Air 1 | 43.3013 | 86.6025 | 2 | 1.33333 | 1.1547 | 1 | 0.333333 | 0.57735 | 550 mmx400 mm-450 mmx350 mm | 200 | 50 | 400 | 350 | 550 | 450 | 0.15731 | 175 | 275 | 225 | 0.0162741 | 100 | 모델 그룹:MEP 2:7855242; 기계 Return Air 1

# IfcFlowFitting: M_직사각형 변환 - 각도:SA, M_직사각형 변환 - 각도:SA:7855272
In: 지상 1층
Type - Material: <Unnamed>
Type - ID 데이터 - OmniClass 번호: 23.75.70.14; OmniClass 제목: Air Ductwork; 유형 이름: SA
Type - 구속조건 - 기본 높이: 0 mm
Type - 기타 - 카테고리: 덕트 부속; 패밀리 이름: M_직사각형 변환 - 각도
Pset_DistributionFlowElementCommon - Reference: SA; sets with these values: 2
공정 - 생성 공정: 새 구성
구속조건 - 레벨: 지상 1층; 각도: 15 deg; 레벨로부터의 높이: 4180 mm
그래픽 - 주석 축척 사용: no
기계 - 시스템 유형: Supply Air; 시스템 분류: 공급 공기; 시스템 이름: 기계 Supply Air 1
기계 - 흐름 - 압력 강하: 0 Pa
기타 - 유형: SA; 델타 1: 0 mm; 패밀리: M_직사각형 변환 - 각도; 번호1: 2; 번호2: 2; 길이 1: 559.808 mm; 길이 2: 379.788 mm; 델타 2: 75 mm; 번호3: 55.7128; 번호4: 7.4641; 번호5: 6; 번호6: 0; 번호7: 125.354; 번호8: 11.1962; 유형 ID: 7855766; 패밀리 및 유형: M_직사각형 변환 - 각도: SA
단열재 - 단열재 두께: 0 mm; 전체 크기: 500 mmx400 mm-400 mmx250 mm
라이닝 - 라이닝 두께: 0 mm; 사용 가능한 크기: 500 mmx400 mm-400 mmx250 mm
치수 - 계산한 길이: 559.808 mm; 높이 간격띄우기: 125; 높이 델타: 150 mm; 덕트 길이: 559.808 mm; 덕트 높이 1: 400 mm; 덕트 높이 2: 250 mm; 덕트 폭 1: 500 mm; 덕트 폭 2: 400 mm; 면적: 0.423813 m2; 절반 높이 1: 200 mm; 절반 높이 2: 125 mm; 절반 폭 1: 250 mm; 절반 폭 2: 200 mm; 체적: 0.0825716 m3; 최대 델타: 559.808 mm; 크기: 500 mmx400 mm-400 mmx250 mm; 폭 간격띄우기: 250; 폭 델타: 100 mm
Group: 모델 그룹:MEP 2:7855242; 기계 Supply Air 1

# IfcFlowFitting: M_직사각형 엘보 - 반지름:RA (8)
In: 지상 1층
Type - Material: <Unnamed>
Type - ID 데이터 - OmniClass 번호: 23.75.70.14; OmniClass 제목: Air Ductwork; 유형 이름: RA
Type - 구속조건 - 기본 높이: 0 mm
Type - 기타 - 카테고리: 덕트 부속; 패밀리 이름: M_직사각형 엘보 - 반지름
Pset_DistributionFlowElementCommon - Reference: RA; sets with these values: 2
공정 - 생성 공정: 새 구성
구속조건 - 레벨: 지상 1층
그래픽 - 주석 축척 사용: no
기계 - 시스템 유형: Return Air; 시스템 분류: 순환 공기
기타 - 유형: RA; 유형 ID: 7855765; 패밀리: M_직사각형 엘보 - 반지름; 패밀리 및 유형: M_직사각형 엘보 - 반지름: RA
단열재 - 단열재 두께: 0 mm
라이닝 - 라이닝 두께: 0 mm
치수 - 각도: 45 deg; 반지름 승수: 1
Name (M_직사각형 엘보 - 반지름:RA:...) | 레벨로부터의 높이 (mm) | 시스템 이름 | 전체 크기 = 사용 가능한 크기 = 크기 | 덕트 길이 1 (mm) | 덕트 높이 (mm) | 덕트 폭 (mm) = 중심 반지름 (mm) | 체적 (m3) | Group
7855275 | 4180 | 기계 Return Air 1 | 350 mmx450 mm-350 mmx450 mm | 144.975 | 450 | 350 | 0.0432952 | 모델 그룹:MEP 2:7855242; 기계 Return Air 1
7855277 | 4680 | 기계 Return Air 1 | 350 mmx450 mm-350 mmx450 mm | 144.975 | 450 | 350 | 0.0432952 | 모델 그룹:MEP 2:7855242; 기계 Return Air 1
7855278 | 4180 | 기계 Return Air 6 | 350 mmx450 mm-350 mmx450 mm | 144.975 | 450 | 350 | 0.0432952 | 모델 그룹:MEP 2:7855242; 기계 Return Air 6
7855279 | 4680 | 기계 Return Air 6 | 350 mmx450 mm-350 mmx450 mm | 144.975 | 450 | 350 | 0.0432952 | 모델 그룹:MEP 2:7855242; 기계 Return Air 6
7855283 | 4180 | 기계 Return Air 6 | 250 mmx400 mm-250 mmx400 mm | 103.553 | 400 | 250 | 0.0196349 | 모델 그룹:MEP 2:7855242; 기계 Return Air 6
7855285 | 4480 | 기계 Return Air 6 | 250 mmx400 mm-250 mmx400 mm | 103.553 | 400 | 250 | 0.0196349 | 모델 그룹:MEP 2:7855242; 기계 Return Air 6
7855286 | 4180 | 기계 Return Air 6 | 250 mmx400 mm-250 mmx400 mm | 103.553 | 400 | 250 | 0.0196349 | 모델 그룹:MEP 2:7855242; 기계 Return Air 6
7855287 | 4480 | 기계 Return Air 6 | 250 mmx400 mm-250 mmx400 mm | 103.553 | 400 | 250 | 0.0196349 | 모델 그룹:MEP 2:7855242; 기계 Return Air 6

# IfcFlowFitting: M_직사각형 탭 - 베벨:RA (2)
In: 지상 1층
Type - Material: <Unnamed>
Type - ID 데이터 - OmniClass 번호: 23.75.70.14; OmniClass 제목: Air Ductwork; 유형 이름: RA
Type - 구속조건 - 기본 높이: 0 mm
Type - 기타 - 카테고리: 덕트 부속; 패밀리 이름: M_직사각형 탭 - 베벨
Pset_DistributionFlowElementCommon - Reference: RA; sets with these values: 2
공정 - 생성 공정: 새 구성
구속조건 - 레벨: 지상 1층; 레벨로부터의 높이: 4180 mm
그래픽 - 주석 축척 사용: no
기계 - 시스템 유형: Return Air; 시스템 분류: 순환 공기
기타 - 패밀리: M_직사각형 탭 - 베벨; 유형: RA; 유형 ID: 7855774; 패밀리 및 유형: M_직사각형 탭 - 베벨: RA; 폭 1: 100 mm
단열재 - 단열재 두께: 0 mm
라이닝 - 라이닝 두께: 0 mm
치수 - 각도: 45 deg; 길이 승수: 0.25; 분지 고정 길이: 100; 분지 길이: 100; 분지 길이 투영: 6.096
Name (M_직사각형 탭 - 베벨:RA:...) | 시스템 이름 | 전체 크기 = 사용 가능한 크기 = 크기 | 덕트 높이 (mm) | 덕트 폭 1 (mm) | 덕트 폭 2 (mm) | 체적 (m3) | Group
7855251 | 기계 Return Air 2 | 300 mmx250 mm-300 mmx250 mm | 250 | 400 | 300 | 0.0093596 | 모델 그룹:MEP 2:7855242; 기계 Return Air 2
7855253 | 기계 Return Air 3 | 250 mmx200 mm-250 mmx200 mm | 200 | 350 | 250 | 0.00642672 | 모델 그룹:MEP 2:7855242; 기계 Return Air 3

# IfcFlowFitting: M_직사각형 탭 - 베벨:SA (2)
In: 지상 1층
Type - Material: <Unnamed>
Type - ID 데이터 - OmniClass 번호: 23.75.70.14; OmniClass 제목: Air Ductwork; 유형 이름: SA
Type - 구속조건 - 기본 높이: 0 mm
Type - 기타 - 카테고리: 덕트 부속; 패밀리 이름: M_직사각형 탭 - 베벨
Pset_DistributionFlowElementCommon - Reference: SA; sets with these values: 2
공정 - 생성 공정: 새 구성
구속조건 - 레벨: 지상 1층; 레벨로부터의 높이: 4180 mm
그래픽 - 주석 축척 사용: no
기계 - 시스템 유형: Supply Air; 시스템 분류: 공급 공기
기타 - 유형: SA; 유형 ID: 7855760; 패밀리: M_직사각형 탭 - 베벨; 패밀리 및 유형: M_직사각형 탭 - 베벨: SA; 폭 1: 100 mm
단열재 - 단열재 두께: 0 mm
라이닝 - 라이닝 두께: 0 mm
치수 - 각도: 45 deg; 길이 승수: 0.25; 분지 고정 길이: 100; 분지 길이: 100; 분지 길이 투영: 6.096
Name (M_직사각형 탭 - 베벨:SA:...) | 시스템 이름 | 전체 크기 = 사용 가능한 크기 = 크기 | 덕트 높이 (mm) | 덕트 폭 1 (mm) | 덕트 폭 2 (mm) | 체적 (m3) | Group
7855246 | 기계 Supply Air 2 | 300 mmx250 mm-300 mmx250 mm | 250 | 400 | 300 | 0.0093596 | 모델 그룹:MEP 2:7855242; 기계 Supply Air 2
7855267 | 기계 Supply Air 4 | 250 mmx200 mm-250 mmx200 mm | 200 | 350 | 250 | 0.00642672 | 모델 그룹:MEP 2:7855242; 기계 Supply Air 4

# IfcFlowSegment: 부속이 있는 케이블 트레이:Ladder Cable Tray (5)
In: 지상 1층
Type - PredefinedType: CABLETRAYSEGMENT
Type - ID 데이터 - 유형 이름: Ladder Cable Tray
Type - 기타 - 카테고리: 케이블 트레이; 패밀리 이름: 부속이 있는 케이블 트레이
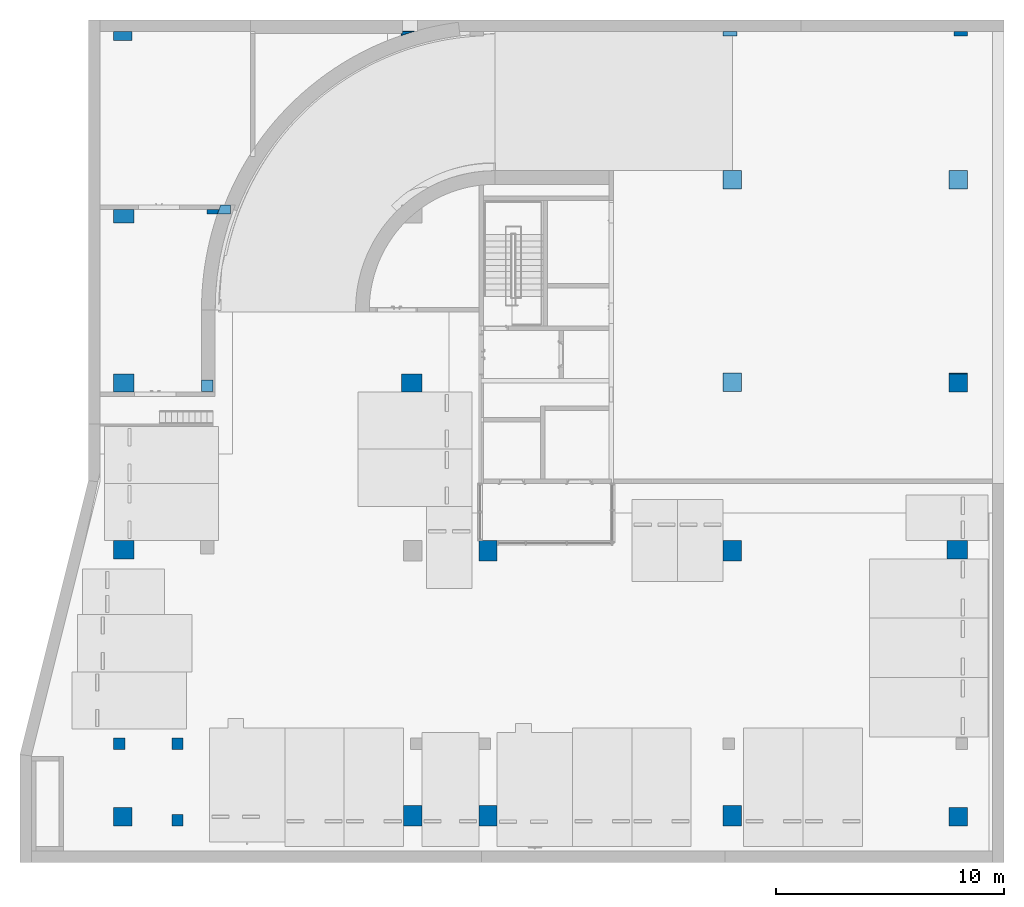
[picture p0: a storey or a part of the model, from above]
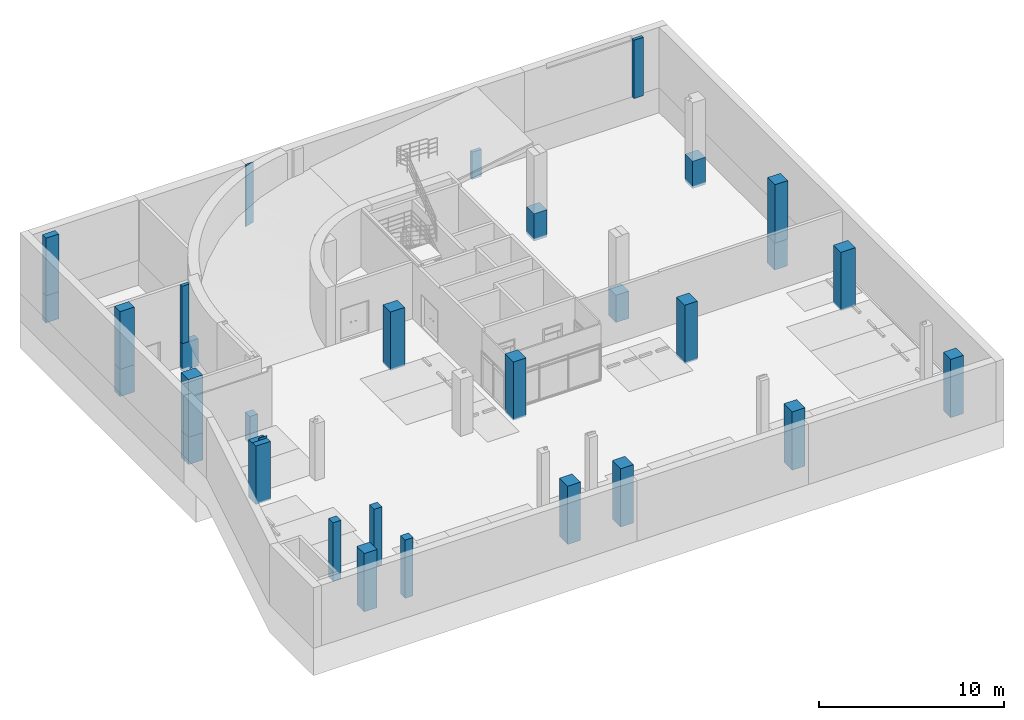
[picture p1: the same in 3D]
Properties of the parts of a building model (IFC2X3), part 13 of 39

# IfcFlowSegment: 부속이 있는 케이블 트레이:Ladder Cable Tray (5)
Type - 부속 - T자형: M_래더 수평 티: 600mm 반지름; 결합: M_래더 결합: 표준; 교차: M_래더 수평 교차: 600mm 반지름; 변환: M_래더 리듀서: 표준; 수직 내부 구부림: M_래더 수직 내부 구부림: 표준; 수직 외부 구부림: M_래더 수직 외부 구부림: 표준; 수평 구부림: M_래더 수평 구부림: 표준
Type - 전기 - 구부림 반지름 승수: 1
Pset_DistributionFlowElementCommon - Reference: Ladder Cable Tray; sets with these values: 2
Pset_FlowSegmentDuctSegment - Length: 100 mm; sets with these values: 2
공정 - 생성 공정: 새 구성
구속조건 - 수직 맞춤: 가운데; 수평 맞춤: 중앙; 참조 레벨: 지상 1층; 바닥면의 하단 높이: 3730 mm; 상단 끝 중심선 높이: 3780 mm; 상단 끝 하단 높이: 3730 mm; 윗면의 상단 높이: 3830 mm; 중간 높이: 3780 mm; 중간 입면도 끝: 3780 mm; 중간 입면도 시작: 3780 mm; 하단 끝 상단 높이: 3830 mm; 하단 끝 중심선 높이: 3780 mm
기타 - 유형: Ladder Cable Tray; 유형 ID: 7855754; 패밀리: 부속이 있는 케이블 트레이; 패밀리 및 유형: 부속이 있는 케이블 트레이: Ladder Cable Tray
치수 - 가로장 공간: 228.6 mm; 높이: 100 mm; 크기: 600 mmx100 mmø; 폭: 600 mm
Group: 모델 그룹:MEP 2:7855242
Name (부속이 있는 케이블 트레이:Ladder Cable Tray:...) | 길이 (mm)
7855331 | 6975.79
7855332 | 5699.17
7855334 | 5699.17
7855336 | 6000
7855338 | 5729.17

# IfcFlowSegment: 원형 덕트:RA (3)
In: 지상 1층
Type - ID 데이터 - 유형 이름: RA
Type - 기타 - 카테고리: 덕트; 패밀리 이름: 원형 덕트
Type - 시공 - 거칠기: 0.09144 mm
Pset_DistributionFlowElementCommon - Reference: RA; sets with these values: 2
Pset_FlowSegmentDuctSegment - sets with these values: 2
Pset_DuctSegmentTypeCommon - Shape: ROUND
공정 - 생성 공정: 새 구성
구속조건 - 경사: 0; 수직 맞춤: 가운데; 수평 맞춤: 중앙; 참조 레벨: 지상 1층; 바닥면의 하단 높이: 4080 mm; 상단 끝 중심선 높이: 4180 mm; 상단 끝 하단 높이: 4080 mm; 윗면의 상단 높이: 4280 mm; 중간 높이: 4180 mm; 중간 입면도 끝: 4180 mm; 중간 입면도 시작: 4180 mm; 하단 끝 상단 높이: 4280 mm; 하단 끝 중심선 높이: 4180 mm
기계 - 단면: 2; 손실 계수: 0; 크기 잠금: no; 시스템 유형: Return Air; 등가 지름: 200 mm; 수압 지름: 200 mm; 시스템 분류: 순환 공기
기계 - 흐름 - 레이놀즈 넘버: 0; 마찰: 0 kg/m2/s2; 속도: 0 m/s; 속도 압력: 0 Pa; 압력 강하: 0 Pa; 유량: 0 m3/s; 추가 흐름: 0 m3/s
기타 - 유형: RA; 유형 ID: 7855780; 패밀리: 원형 덕트; 패밀리 및 유형: 원형 덕트: RA
단열재 - 단열재 두께: 0 mm; 단열재 높이의 상단 끝 하단: 4080 mm; 단열재 높이의 하단 끝 상단: 4280 mm; 단열재 바닥면의 하단: 4080 mm; 단열재 상부면의 상단: 4280 mm; 전체 크기: 200 mm
라이닝 - 라이닝 두께: 0 mm; 사용 가능한 크기: 200 mm
치수 - 지름: 200 mm; 크기: 200 mm
Name (원형 덕트:RA:...) | Pset_FlowSegmentDuctSegment, Length (mm) = Pset_DuctSegmentTypeCommon, Length (mm) = 길이 (mm) | 면적 (m2) | 시스템 이름 | Group
7855258 | 2970.07 | 1.86615 | 기계 Return Air 8 | 모델 그룹:MEP 2:7855242; 기계 Return Air 8
7855260 | 4326.75 | 2.71858 | 기계 Return Air 8 | 모델 그룹:MEP 2:7855242; 기계 Return Air 8
7855262 | 4226.75 | 2.65574 | 기계 Return Air 7 | 모델 그룹:MEP 2:7855242; 기계 Return Air 7

# IfcFlowSegment: 직사각형 덕트:RA (12)
In: 지상 1층
Type - ID 데이터 - 유형 이름: RA
Type - 기타 - 카테고리: 덕트; 패밀리 이름: 직사각형 덕트
Type - 시공 - 거칠기: 0.09144 mm
Pset_DistributionFlowElementCommon - Reference: RA; sets with these values: 2
Pset_FlowSegmentDuctSegment - sets with these values: 3
공정 - 생성 공정: 새 구성
구속조건 - 수직 맞춤: 가운데; 수평 맞춤: 중앙; 참조 레벨: 지상 1층
기계 - 손실 계수: 0; 크기 잠금: no; 시스템 분류: 순환 공기; 시스템 유형: Return Air
기계 - 흐름 - 레이놀즈 넘버: 0; 마찰: 0 kg/m2/s2; 속도: 0 m/s; 속도 압력: 0 Pa; 압력 강하: 0 Pa; 유량: 0 m3/s; 추가 흐름: 0 m3/s
기타 - 패밀리: 직사각형 덕트; 유형: RA; 유형 ID: 7855758; 패밀리 및 유형: 직사각형 덕트: RA
단열재 - 단열재 두께: 0 mm
라이닝 - 라이닝 두께: 0 mm
Name (직사각형 덕트:RA:...) | Length (mm) | 경사 | 바닥면의 하단 높이 (mm) = 단열재 바닥면의 하단 (mm) | 상단 끝 중심선 높이 (mm) | 상단 끝 하단 높이 (mm) = 단열재 높이의 상단 끝 하단 (mm) | 윗면의 상단 높이 (mm) = 단열재 상부면의 상단 (mm) | 중간 높이 (mm) = 중간 입면도 시작 (mm) | 중간 입면도 끝 (mm) | 하단 끝 상단 높이 (mm) = 단열재 높이의 하단 끝 상단 (mm) | 하단 끝 중심선 높이 (mm) | 단면 | 등가 지름 (mm) | 면적 (m2) | 수압 지름 (mm) | 시스템 이름 | 전체 크기 = 사용 가능한 크기 = 크기 | 길이 (mm) | 높이 (mm) | 폭 (mm) | Group
7855247 | 400 | 0 | 3980 | 4180 | 3980 | 4380 | 4180 | 4180 | 4380 | 4180 | 4 | 511.124 | 7.3956 | 463.158 | 기계 Return Air 1 | 550 mmx400 mm | 3892.42 | 400 | 550 | 모델 그룹:MEP 2:7855242; 기계 Return Air 1
7855248 | 350 | 0 | 4005 | 4180 | 4005 | 4355 | 4180 | 4180 | 4355 | 4180 | 2 | 432.983 | 4.59854 | 393.75 | 기계 Return Air 6 | 450 mmx350 mm | 2874.09 | 350 | 450 | 모델 그룹:MEP 2:7855242; 기계 Return Air 6
7855249 | 250 | 0 | 4055 | 4180 | 4055 | 4305 | 4180 | 4180 | 4305 | 4180 | 1 | 343.333 | 4.95987 | 307.692 | 기계 Return Air 6 | 400 mmx250 mm | 3815.28 | 250 | 400 | 모델 그룹:MEP 2:7855242; 기계 Return Air 6
7855250 | 250 | 0 | 4055 | 4180 | 4055 | 4305 | 4180 | 4180 | 4305 | 4180 | 22 | 299.065 | 4.88532 | 272.727 | 기계 Return Air 2 | 300 mmx250 mm | 4441.2 | 250 | 300 | 모델 그룹:MEP 2:7855242; 기계 Return Air 2
7855252 | 200 | 0 | 4080 | 4180 | 4080 | 4280 | 4180 | 4180 | 4280 | 4180 | 25 | 244.06 | 3.50312 | 222.222 | 기계 Return Air 3 | 250 mmx200 mm | 3892.36 | 200 | 250 | 모델 그룹:MEP 2:7855242; 기계 Return Air 3
7855273 | 350 | 0 | 4005 | 4180 | 4005 | 4355 | 4180 | 4180 | 4355 | 4180 | 33 | 432.983 | 0.822727 | 393.75 | 기계 Return Air 1 | 450 mmx350 mm | 514.205 | 350 | 450 | 모델 그룹:MEP 2:7855242; 기계 Return Air 1
7855274 | 450 | 100 | 4158.77 | 4577.49 | 4453.74 | 4701.23 | 4282.51 | 4577.49 | 4406.26 | 4282.51 | 33 | 432.983 | 0.667452 | 393.75 | 기계 Return Air 1 | 450 mmx350 mm | 417.157 | 350 | 450 | 모델 그룹:MEP 2:7855242; 기계 Return Air 1
7855276 | 450 | 100 | 4158.77 | 4577.49 | 4453.74 | 4701.23 | 4282.51 | 4577.49 | 4406.26 | 4282.51 | 2 | 432.983 | 0.667452 | 393.75 | 기계 Return Air 6 | 450 mmx350 mm | 417.157 | 350 | 450 | 모델 그룹:MEP 2:7855242; 기계 Return Air 6
7855280 | 250 | 0 | 4055 | 4180 | 4055 | 4305 | 4180 | 4180 | 4305 | 4180 | 1 | 343.333 | 3.81348 | 307.692 | 기계 Return Air 6 | 400 mmx250 mm | 2933.45 | 250 | 400 | 모델 그룹:MEP 2:7855242; 기계 Return Air 6
7855281 | 250 | 0 | 4355 | 4480 | 4355 | 4605 | 4480 | 4480 | 4605 | 4480 | 1 | 343.333 | 1.01104 | 307.692 | 기계 Return Air 6 | 400 mmx250 mm | 777.72 | 250 | 400 | 모델 그룹:MEP 2:7855242; 기계 Return Air 6
7855282 | 400 | 100 | 4164.83 | 4406.78 | 4318.39 | 4495.17 | 4406.78 | 4253.22 | 4341.61 | 4253.22 | 1 | 343.333 | 0.282304 | 307.692 | 기계 Return Air 6 | 400 mmx250 mm | 217.157 | 250 | 400 | 모델 그룹:MEP 2:7855242; 기계 Return Air 6
7855284 | 400 | 100 | 4164.83 | 4406.78 | 4318.39 | 4495.17 | 4253.22 | 4406.78 | 4341.61 | 4253.22 | 1 | 343.333 | 0.282304 | 307.692 | 기계 Return Air 6 | 400 mmx250 mm | 217.157 | 250 | 400 | 모델 그룹:MEP 2:7855242; 기계 Return Air 6

# IfcFlowSegment: 직사각형 덕트:SA (4)
In: 지상 1층
Type - ID 데이터 - 유형 이름: SA
Type - 기타 - 카테고리: 덕트; 패밀리 이름: 직사각형 덕트
Type - 시공 - 거칠기: 0.09144 mm
Pset_DistributionFlowElementCommon - Reference: SA; sets with these values: 2
Pset_FlowSegmentDuctSegment - sets with these values: 3
공정 - 생성 공정: 새 구성
구속조건 - 경사: 0; 수직 맞춤: 가운데; 수평 맞춤: 중앙; 참조 레벨: 지상 1층
기계 - 손실 계수: 0; 시스템 분류: 공급 공기; 시스템 유형: Supply Air; 크기 잠금: no
기계 - 흐름 - 레이놀즈 넘버: 0; 마찰: 0 kg/m2/s2; 속도: 0 m/s; 속도 압력: 0 Pa; 압력 강하: 0 Pa; 유량: 0 m3/s; 추가 흐름: 0 m3/s
기타 - 유형: SA; 유형 ID: 7855752; 패밀리: 직사각형 덕트; 패밀리 및 유형: 직사각형 덕트: SA
단열재 - 단열재 두께: 0 mm
라이닝 - 라이닝 두께: 0 mm
Name (직사각형 덕트:SA:...) | Length (mm) = 높이 (mm) | 바닥면의 하단 높이 (mm) = 상단 끝 하단 높이 (mm) = 단열재 높이의 상단 끝 하단 (mm) = 단열재 바닥면의 하단 (mm) | 상단 끝 중심선 높이 (mm) = 중간 높이 (mm) = 중간 입면도 끝 (mm) = 중간 입면도 시작 (mm) = 하단 끝 중심선 높이 (mm) | 윗면의 상단 높이 (mm) = 하단 끝 상단 높이 (mm) = 단열재 높이의 하단 끝 상단 (mm) = 단열재 상부면의 상단 (mm) | 단면 | 등가 지름 (mm) | 면적 (m2) | 수압 지름 (mm) | 시스템 이름 | 전체 크기 = 사용 가능한 크기 = 크기 | 길이 (mm) | 폭 (mm) | Group
7855243 | 250 | 3980 | 4105 | 4230 | 2 | 343.333 | 3.72475 | 307.692 | 기계 Supply Air 1 | 400 mmx250 mm | 2865.19 | 400 | 모델 그룹:MEP 2:7855242; 기계 Supply Air 1
7855244 | 400 | 3980 | 4180 | 4380 | 3 | 488.12 | 25.1864 | 444.444 | 기계 Supply Air 1 | 500 mmx400 mm | 13992.4 | 500 | 모델 그룹:MEP 2:7855242; 기계 Supply Air 1
7855245 | 250 | 4055 | 4180 | 4305 | 10 | 299.065 | 8.05623 | 272.727 | 기계 Supply Air 2 | 300 mmx250 mm | 7323.84 | 300 | 모델 그룹:MEP 2:7855242; 기계 Supply Air 2
7855266 | 200 | 4080 | 4180 | 4280 | 4 | 244.06 | 6.01875 | 222.222 | 기계 Supply Air 4 | 250 mmx200 mm | 6687.5 | 250 | 모델 그룹:MEP 2:7855242; 기계 Supply Air 4

# IfcFlowSegment: 플렉시블 덕트 원형:RA (9)
In: 지상 1층
Type - PredefinedType: FLEXIBLESEGMENT
Type - ID 데이터 - 유형 이름: RA
Type - 기타 - 카테고리: 플렉시블 덕트; 패밀리 이름: 플렉시블 덕트 원형
Type - 부속 - 기본 접합 유형: 탭; 탭: M_원형 견적: RA
Type - 시공 - 거칠기: 0.09144 mm
Pset_DistributionFlowElementCommon - Reference: RA; sets with these values: 2
공정 - 생성 공정: 새 구성
구속조건 - 참조 레벨: 지상 1층
그래픽 - 절연 패턴: 단일 선
기계 - 손실 계수: 0; 크기 잠금: no; 시스템 유형: Return Air; 등가 지름: 150 mm; 수압 지름: 150 mm; 시스템 분류: 순환 공기
기계 - 흐름 - 레이놀즈 넘버: 0; 마찰: 0 kg/m2/s2; 속도: 0 m/s; 속도 압력: 0 Pa; 압력 강하: 0 Pa; 유량: 0 m3/s; 추가 흐름: 0 m3/s
기타 - 유형: RA; 패밀리: 플렉시블 덕트 원형; 유형 ID: 7855798; 패밀리 및 유형: 플렉시블 덕트 원형: RA
단열재 - 단열재 두께: 0 mm; 전체 크기: 150 mm
라이닝 - 라이닝 두께: 0 mm; 사용 가능한 크기: 150 mm
치수 - 지름: 150 mm
Name (플렉시블 덕트 원형:RA:...) | 중간 입면도 시작 (mm) | 단면 | 시스템 이름 | 길이 (mm) | Group
7855297 | 37640 | 10 | 기계 Return Air 14 | 749.023 | 모델 그룹:MEP 2:7855242; 기계 Return Air 14
7855300 | 37640 | 11 | 기계 Return Air 16 | 749.023 | 모델 그룹:MEP 2:7855242; 기계 Return Air 16
7855303 | 37640 | 13 | 기계 Return Air 18 | 749.023 | 모델 그룹:MEP 2:7855242; 기계 Return Air 18
7855306 | 37534 | 26 | 기계 Return Air 20 | 944.764 | 모델 그룹:MEP 2:7855242; 기계 Return Air 20
7855309 | 37534 | 27 | 기계 Return Air 22 | 944.785 | 모델 그룹:MEP 2:7855242; 기계 Return Air 22
7855318 | 37640 | 3 | 기계 Return Air 24 | 1042.48 | 모델 그룹:MEP 2:7855242; 기계 Return Air 24
7855321 | 37640 | 4 | 기계 Return Air 26 | 1041.91 | 모델 그룹:MEP 2:7855242; 기계 Return Air 26
7855324 | 38080 | 3 | 기계 Return Air 28 | 770.809 | 모델 그룹:MEP 2:7855242; 기계 Return Air 28
7855327 | 38080 | 4 | 기계 Return Air 30 | 766.672 | 모델 그룹:MEP 2:7855242; 기계 Return Air 30

# IfcFlowSegment: 플렉시블 덕트 원형:SA (5)
In: 지상 1층
Type - PredefinedType: FLEXIBLESEGMENT
Type - ID 데이터 - 유형 이름: SA
Type - 기타 - 카테고리: 플렉시블 덕트; 패밀리 이름: 플렉시블 덕트 원형
Type - 부속 - 기본 접합 유형: 탭; 탭: M_원형 견적: SA
Type - 시공 - 거칠기: 0.09144 mm
Pset_DistributionFlowElementCommon - Reference: SA; sets with these values: 2
공정 - 생성 공정: 새 구성
구속조건 - 참조 레벨: 지상 1층
그래픽 - 절연 패턴: 단일 선
기계 - 손실 계수: 0; 시스템 유형: Supply Air; 크기 잠금: no; 등가 지름: 150 mm; 수압 지름: 150 mm; 시스템 분류: 공급 공기
기계 - 흐름 - 레이놀즈 넘버: 0; 마찰: 0 kg/m2/s2; 속도: 0 m/s; 속도 압력: 0 Pa; 압력 강하: 0 Pa; 유량: 0 m3/s; 추가 흐름: 0 m3/s
기타 - 유형: SA; 유형 ID: 7855753; 패밀리: 플렉시블 덕트 원형; 패밀리 및 유형: 플렉시블 덕트 원형: SA
단열재 - 단열재 두께: 0 mm; 전체 크기: 150 mm
라이닝 - 라이닝 두께: 0 mm; 사용 가능한 크기: 150 mm
치수 - 지름: 150 mm
Name (플렉시블 덕트 원형:SA:...) | 중간 입면도 시작 (mm) | 단면 | 시스템 이름 | 길이 (mm) | Group
7855288 | 37640 | 11 | 기계 Supply Air 6 | 747.598 | 모델 그룹:MEP 2:7855242; 기계 Supply Air 6
7855291 | 37640 | 12 | 기계 Supply Air 8 | 747.598 | 모델 그룹:MEP 2:7855242; 기계 Supply Air 8
7855294 | 37640 | 14 | 기계 Supply Air 10 | 747.598 | 모델 그룹:MEP 2:7855242; 기계 Supply Air 10
7855312 | 37534 | 6 | 기계 Supply Air 12 | 944.735 | 모델 그룹:MEP 2:7855242; 기계 Supply Air 12
7855315 | 37534 | 7 | 기계 Supply Air 14 | 944.785 | 모델 그룹:MEP 2:7855242; 기계 Supply Air 14

# IfcFlowTerminal: PF127-서양식 탱크일체형:PF127-서양식 탱크일체형 (40)
Type - Material: KBIMS-스테인리스 스틸_도금, KBIMS-도기 (2)
Type - ID 데이터 - OmniClass 번호: 23.75.00.00; OmniClass 제목: Climate Control (HVAC); 단가: 0; 유형 이름: PF127-서양식 탱크일체형
Type - 구속조건 - 기본 높이: 0 mm
Type - 기계 - CWFU: 0; HWFU: 0; WFU: 0
Type - 기타 - 카테고리: 위생기구; KBIMS-부위코드: E71210; 제작정보: bSK-2021_KBIMS2.0-bC; 조달청표준공사코드: MHA11110020S; 패밀리 이름: PF127-서양식 탱크일체형
Type - 치수 - 가로: 400 mm; 높이: 720 mm; 세로: 700 mm
Pset_DistributionFlowElementCommon - Reference: PF127-서양식 탱크일체형; sets with these values: 2
공정 - 생성 공정: 새 구성
구속조건 - 가까운 요소로 이동: no; 호스트에서의 간격띄우기: 0 mm
기타 - 유형: PF127-서양식 탱크일체형; 유형 ID: 6449337; 패밀리: PF127-서양식 탱크일체형; 패밀리 및 유형: PF127-서양식 탱크일체형: PF127-서양식 탱크일체형
치수 - 면적: 0.996879 m2; 체적: 0.112542 m3
Name (PF127-서양식 탱크일체형:PF127-서양식 탱크일체형:...) | In | 마크 | 레벨 | 레벨로부터의 높이 (mm) | 호스트 | Material
3145933 | 188 | 8 | 지상 2층 | 0 | 레벨 : 지상 2층
3145934 | 188 | 9 | 지상 2층 | 0 | 레벨 : 지상 2층 | KBIMS-스테인리스 스틸_도금, KBIMS-도기
3145935 | 188 | 10 | 지상 2층 | 0 | 레벨 : 지상 2층 | KBIMS-스테인리스 스틸_도금, KBIMS-도기
3145944 | 189 | 19 | 지상 2층 | 0 | 레벨 : 지상 2층 | KBIMS-스테인리스 스틸_도금, KBIMS-도기
3146187 | 170 | 22 | 지상 1층 | -510 | 바닥 : A1-14-03A-시멘트모르타르(고름용), 도막방수, 시멘트모르타르(보호용), 자기질타일 (90mm) | KBIMS-스테인리스 스틸_도금, KBIMS-도기
3146188 | 170 | 23 | 지상 1층 | -510 | 바닥 : A1-14-03A-시멘트모르타르(고름용), 도막방수, 시멘트모르타르(보호용), 자기질타일 (90mm) | KBIMS-스테인리스 스틸_도금, KBIMS-도기
3146189 | 170 | 24 | 지상 1층 | -510 | 바닥 : A1-14-03A-시멘트모르타르(고름용), 도막방수, 시멘트모르타르(보호용), 자기질타일 (90mm) | KBIMS-스테인리스 스틸_도금, KBIMS-도기
3146198 | 171 | 33 | 지상 1층 | -510 | 바닥 : A1-14-03A-시멘트모르타르(고름용), 도막방수, 시멘트모르타르(보호용), 자기질타일 (90mm) | KBIMS-스테인리스 스틸_도금, KBIMS-도기
3146246 | 202 | 36 | 지상 3층 | 0 | 레벨 : 지상 3층 | KBIMS-스테인리스 스틸_도금, KBIMS-도기
3146247 | 202 | 37 | 지상 3층 | 0 | 레벨 : 지상 3층 | KBIMS-스테인리스 스틸_도금, KBIMS-도기
3146248 | 202 | 38 | 지상 3층 | 0 | 레벨 : 지상 3층 | KBIMS-스테인리스 스틸_도금, KBIMS-도기
3146257 | 203 | 47 | 지상 3층 | 0 | 레벨 : 지상 3층 | KBIMS-스테인리스 스틸_도금, KBIMS-도기
3146305 | 222 | 50 | 지상 4층 | 0 | 레벨 : 지상 4층 | KBIMS-스테인리스 스틸_도금, KBIMS-도기
3146306 | 222 | 51 | 지상 4층 | 0 | 레벨 : 지상 4층 | KBIMS-스테인리스 스틸_도금, KBIMS-도기
3146307 | 222 | 52 | 지상 4층 | 0 | 레벨 : 지상 4층 | KBIMS-스테인리스 스틸_도금, KBIMS-도기
3146316 | 221 | 74 | 지상 4층 | 0 | 레벨 : 지상 4층 | KBIMS-스테인리스 스틸_도금, KBIMS-도기
3146364 | 225 | 77 | 지상 5층 | 0 | 레벨 : 지상 5층 | KBIMS-스테인리스 스틸_도금, KBIMS-도기
3146365 | 225 | 78 | 지상 5층 | 0 | 레벨 : 지상 5층 | KBIMS-스테인리스 스틸_도금, KBIMS-도기
3146366 | 225 | 79 | 지상 5층 | 0 | 레벨 : 지상 5층 | KBIMS-스테인리스 스틸_도금, KBIMS-도기
3146375 | 226 | 88 | 지상 5층 | 0 | 레벨 : 지상 5층 | KBIMS-스테인리스 스틸_도금, KBIMS-도기
3146423 | 240 | 91 | 지상 6층 | 0 | 레벨 : 지상 6층 | KBIMS-스테인리스 스틸_도금, KBIMS-도기
3146424 | 240 | 92 | 지상 6층 | 0 | 레벨 : 지상 6층 | KBIMS-스테인리스 스틸_도금, KBIMS-도기
3146425 | 240 | 93 | 지상 6층 | 0 | 레벨 : 지상 6층 | KBIMS-스테인리스 스틸_도금, KBIMS-도기
3146434 | 241 | 102 | 지상 6층 | 0 | 레벨 : 지상 6층 | KBIMS-스테인리스 스틸_도금, KBIMS-도기
3146482 | 266 | 105 | 지상 7층 | 0 | 레벨 : 지상 7층 | KBIMS-스테인리스 스틸_도금, KBIMS-도기
3146483 | 266 | 106 | 지상 7층 | 0 | 레벨 : 지상 7층 | KBIMS-스테인리스 스틸_도금, KBIMS-도기
3146484 | 266 | 107 | 지상 7층 | 0 | 레벨 : 지상 7층 | KBIMS-스테인리스 스틸_도금, KBIMS-도기
3146493 | 267 | 116 | 지상 7층 | 0 | 레벨 : 지상 7층 | KBIMS-스테인리스 스틸_도금, KBIMS-도기
3146541 | 278 | 119 | 지상 8층 | 0 | 레벨 : 지상 8층 | KBIMS-스테인리스 스틸_도금, KBIMS-도기
3146542 | 278 | 120 | 지상 8층 | 0 | 레벨 : 지상 8층 | KBIMS-스테인리스 스틸_도금, KBIMS-도기
3146543 | 278 | 121 | 지상 8층 | 0 | 레벨 : 지상 8층 | KBIMS-스테인리스 스틸_도금, KBIMS-도기
3146552 | 279 | 130 | 지상 8층 | 0 | 레벨 : 지상 8층 | KBIMS-스테인리스 스틸_도금, KBIMS-도기
3146600 | 297 | 133 | 지상 9층 | 0 | 레벨 : 지상 9층 | KBIMS-스테인리스 스틸_도금, KBIMS-도기
3146601 | 297 | 134 | 지상 9층 | 0 | 레벨 : 지상 9층 | KBIMS-스테인리스 스틸_도금, KBIMS-도기
3146602 | 297 | 135 | 지상 9층 | 0 | 레벨 : 지상 9층 | KBIMS-스테인리스 스틸_도금, KBIMS-도기
3146611 | 298 | 144 | 지상 9층 | 0 | 레벨 : 지상 9층 | KBIMS-스테인리스 스틸_도금, KBIMS-도기
3146659 | 312 | 147 | 지상 10층 | 0 | 레벨 : 지상 10층 | KBIMS-스테인리스 스틸_도금, KBIMS-도기
3146660 | 312 | 148 | 지상 10층 | 0 | 레벨 : 지상 10층 | KBIMS-스테인리스 스틸_도금, KBIMS-도기
3146661 | 312 | 149 | 지상 10층 | 0 | 레벨 : 지상 10층 | KBIMS-스테인리스 스틸_도금, KBIMS-도기
3146670 | 313 | 158 | 지상 10층 | 0 | 레벨 : 지상 10층 | KBIMS-스테인리스 스틸_도금, KBIMS-도기

# IfcFlowTerminal: PF141-장애인용 대변기:PF141-장애인용 대변기 (20)
Type - Material: KBIMS-스테인리스 스틸_도금
Type - ID 데이터 - OmniClass 번호: 23.75.00.00; OmniClass 제목: Climate Control (HVAC); 단가: 0; 유형 이름: PF141-장애인용 대변기
Type - 구속조건 - 기본 높이: 0 mm
Type - 기계 - CWFU: 0; HWFU: 0; WFU: 0
Type - 기타 - 카테고리: 위생기구; KBIMS-부위코드: E71210; 제작정보: bSK-2021_KBIMS2.0-bC; 조달청표준공사코드: MHA141001000; 패밀리 이름: PF141-장애인용 대변기
Type - 치수 - 가로: 365 mm; 높이: 420 mm; 세로: 670 mm
Material: KBIMS-스테인리스 스틸_도금, KBIMS-도기
Pset_DistributionFlowElementCommon - Reference: PF141-장애인용 대변기; sets with these values: 2
공정 - 생성 공정: 새 구성
구속조건 - 가까운 요소로 이동: no; 호스트에서의 간격띄우기: 0 mm
기타 - 유형: PF141-장애인용 대변기; 유형 ID: 7202402; 패밀리: PF141-장애인용 대변기; 패밀리 및 유형: PF141-장애인용 대변기: PF141-장애인용 대변기
치수 - 면적: 0.844748 m2; 체적: 0.0544312 m3
Name (PF141-장애인용 대변기:PF141-장애인용 대변기:...) | In | 마크 | 레벨 | 레벨로부터의 높이 (mm) | 호스트
3145938 | 188 | 13 | 지상 2층 | 0 | 레벨 : 지상 2층
3145943 | 189 | 18 | 지상 2층 | 0 | 레벨 : 지상 2층
3146192 | 170 | 27 | 지상 1층 | -510 | 바닥 : A1-14-03A-시멘트모르타르(고름용), 도막방수, 시멘트모르타르(보호용), 자기질타일 (90mm)
3146197 | 171 | 32 | 지상 1층 | -510 | 바닥 : A1-14-03A-시멘트모르타르(고름용), 도막방수, 시멘트모르타르(보호용), 자기질타일 (90mm)
3146251 | 202 | 41 | 지상 3층 | 0 | 레벨 : 지상 3층
3146256 | 203 | 46 | 지상 3층 | 0 | 레벨 : 지상 3층
3146310 | 222 | 68 | 지상 4층 | 0 | 레벨 : 지상 4층
3146315 | 221 | 73 | 지상 4층 | 0 | 레벨 : 지상 4층
3146369 | 225 | 82 | 지상 5층 | 0 | 레벨 : 지상 5층
3146374 | 226 | 87 | 지상 5층 | 0 | 레벨 : 지상 5층
3146428 | 240 | 96 | 지상 6층 | 0 | 레벨 : 지상 6층
3146433 | 241 | 101 | 지상 6층 | 0 | 레벨 : 지상 6층
3146487 | 266 | 110 | 지상 7층 | 0 | 레벨 : 지상 7층
3146492 | 267 | 115 | 지상 7층 | 0 | 레벨 : 지상 7층
3146546 | 278 | 124 | 지상 8층 | 0 | 레벨 : 지상 8층
3146551 | 279 | 129 | 지상 8층 | 0 | 레벨 : 지상 8층
3146605 | 297 | 138 | 지상 9층 | 0 | 레벨 : 지상 9층
3146610 | 298 | 143 | 지상 9층 | 0 | 레벨 : 지상 9층
3146664 | 312 | 152 | 지상 10층 | 0 | 레벨 : 지상 10층
3146669 | 313 | 157 | 지상 10층 | 0 | 레벨 : 지상 10층

# IfcFlowTerminal: PF213-스톨형 소변기:PF213-스톨형 소변기 (10)
Type - Material: KBIMS-도기, KBIMS-스테인리스 스틸_도금
Type - ID 데이터 - OmniClass 번호: 23.75.00.00; OmniClass 제목: Climate Control (HVAC); 단가: 0; 유형 이름: PF213-스톨형 소변기
Type - 구속조건 - 기본 높이: 0 mm
Type - 기계 - CWFU: 0; HWFU: 0; WFU: 0
Type - 기타 - 카테고리: 위생기구; KBIMS-부위코드: E71215E71215; 제작정보: bSK-2021_KBIMS2.0-bC; 조달청표준공사코드: MHA32110010S; 패밀리 이름: PF213-스톨형 소변기
Type - 치수 - 가로: 380 mm; 높이: 1070 mm; 세로: 380 mm
Pset_DistributionFlowElementCommon - Reference: PF213-스톨형 소변기; sets with these values: 2
공정 - 생성 공정: 새 구성
구속조건 - 가까운 요소로 이동: no; 호스트에서의 간격띄우기: 0 mm
기타 - 유형: PF213-스톨형 소변기; 유형 ID: 6429598; 패밀리: PF213-스톨형 소변기; 패밀리 및 유형: PF213-스톨형 소변기: PF213-스톨형 소변기
치수 - 면적: 0.801086 m2; 체적: 0.0522931 m3
Name (PF213-스톨형 소변기:PF213-스톨형 소변기:...) | In | 마크 | 레벨 | 레벨로부터의 높이 (mm) | 호스트
3145942 | 189 | 17 | 지상 2층 | 0 | 레벨 : 지상 2층
3146196 | 171 | 31 | 지상 1층 | -510 | 바닥 : A1-14-03A-시멘트모르타르(고름용), 도막방수, 시멘트모르타르(보호용), 자기질타일 (90mm)
3146255 | 203 | 45 | 지상 3층 | 0 | 레벨 : 지상 3층
3146314 | 221 | 72 | 지상 4층 | 0 | 레벨 : 지상 4층
3146373 | 226 | 86 | 지상 5층 | 0 | 레벨 : 지상 5층
3146432 | 241 | 100 | 지상 6층 | 0 | 레벨 : 지상 6층
3146491 | 267 | 114 | 지상 7층 | 0 | 레벨 : 지상 7층
3146550 | 279 | 128 | 지상 8층 | 0 | 레벨 : 지상 8층
3146609 | 298 | 142 | 지상 9층 | 0 | 레벨 : 지상 9층
3146668 | 313 | 156 | 지상 10층 | 0 | 레벨 : 지상 10층

# IfcFlowTerminal: PF231-장애인용 소변기:PF231-장애인용 소변기 (10)
Type - Material: KBIMS-스테인리스 스틸_도금 (2), KBIMS-도기
Type - ID 데이터 - OmniClass 번호: 23.75.00.00; OmniClass 제목: Climate Control (HVAC); 단가: 0; 유형 이름: PF231-장애인용 소변기
Type - 구속조건 - 기본 높이: 0 mm
Type - 기계 - CWFU: 0; HWFU: 0; WFU: 0
Type - 기타 - 카테고리: 위생기구; KBIMS-부위코드: E71215; 제작정보: bSK-2021_KBIMS2.0-bC; 조달청표준공사코드: MHA32110120S; 패밀리 이름: PF231-장애인용 소변기
Type - 치수 - 가로: 380 mm; 높이: 1070 mm; 세로: 380 mm
Pset_DistributionFlowElementCommon - Reference: PF231-장애인용 소변기; sets with these values: 2
공정 - 생성 공정: 새 구성
구속조건 - 가까운 요소로 이동: no; 호스트에서의 간격띄우기: 0 mm
기타 - 유형: PF231-장애인용 소변기; 유형 ID: 6432497; 패밀리: PF231-장애인용 소변기; 패밀리 및 유형: PF231-장애인용 소변기: PF231-장애인용 소변기
치수 - 면적: 1.02096 m2; 체적: 0.0560566 m3
Name (PF231-장애인용 소변기:PF231-장애인용 소변기:...) | In | 마크 | 레벨 | 레벨로부터의 높이 (mm) | 호스트 | Material
3145941 | 189 | 16 | 지상 2층 | 0 | 레벨 : 지상 2층
3146195 | 171 | 30 | 지상 1층 | -510 | 바닥 : A1-14-03A-시멘트모르타르(고름용), 도막방수, 시멘트모르타르(보호용), 자기질타일 (90mm) | KBIMS-스테인리스 스틸_도금, KBIMS-도기
3146254 | 203 | 44 | 지상 3층 | 0 | 레벨 : 지상 3층 | KBIMS-스테인리스 스틸_도금, KBIMS-도기
3146313 | 221 | 71 | 지상 4층 | 0 | 레벨 : 지상 4층 | KBIMS-스테인리스 스틸_도금, KBIMS-도기
3146372 | 226 | 85 | 지상 5층 | 0 | 레벨 : 지상 5층 | KBIMS-스테인리스 스틸_도금, KBIMS-도기
3146431 | 241 | 99 | 지상 6층 | 0 | 레벨 : 지상 6층 | KBIMS-스테인리스 스틸_도금, KBIMS-도기
3146490 | 267 | 113 | 지상 7층 | 0 | 레벨 : 지상 7층 | KBIMS-스테인리스 스틸_도금, KBIMS-도기
3146549 | 279 | 127 | 지상 8층 | 0 | 레벨 : 지상 8층 | KBIMS-스테인리스 스틸_도금, KBIMS-도기
3146608 | 298 | 141 | 지상 9층 | 0 | 레벨 : 지상 9층 | KBIMS-스테인리스 스틸_도금, KBIMS-도기
3146667 | 313 | 155 | 지상 10층 | 0 | 레벨 : 지상 10층 | KBIMS-스테인리스 스틸_도금, KBIMS-도기

# IfcFlowTerminal: PF411-평면붙임형 세면기:PF411-평면붙임형 세면기 (40)
Type - Material: KBIMS-스테인리스 스틸_도금, KBIMS-도기
Type - ID 데이터 - OmniClass 번호: 23.75.00.00; OmniClass 제목: Climate Control (HVAC); 단가: 0; 유형 이름: PF411-평면붙임형 세면기
Type - 구속조건 - 기본 높이: 0 mm
Type - 기계 - CWFU: 0; HWFU: 0; WFU: 0
Type - 기타 - 카테고리: 위생기구; KBIMS-부위코드: E71225; 제작정보: bSK-2021_KBIMS2.0-bC; 조달청표준공사코드: MHA4; 패밀리 이름: PF411-평면붙임형 세면기
Type - 치수 - 가로: 530 mm; 높이: 280 mm; 세로: 500 mm
Pset_DistributionFlowElementCommon - Reference: PF411-평면붙임형 세면기; sets with these values: 2
공정 - 생성 공정: 새 구성
구속조건 - 가까운 요소로 이동: no; 호스트에서의 간격띄우기: 0 mm
기타 - 유형: PF411-평면붙임형 세면기; 유형 ID: 6436009; 패밀리: PF411-평면붙임형 세면기; 패밀리 및 유형: PF411-평면붙임형 세면기: PF411-평면붙임형 세면기
치수 - 면적: 0.594821 m2; 체적: 0.0323312 m3
Name (PF411-평면붙임형 세면기:PF411-평면붙임형 세면기:...) | In | 마크 | 레벨 | 레벨로부터의 높이 (mm) | 호스트
3145945 | 189 | 20 | 지상 2층 | 0 | 레벨 : 지상 2층
3146193 | 170 | 28 | 지상 1층 | -510 | 바닥 : A1-14-03A-시멘트모르타르(고름용), 도막방수, 시멘트모르타르(보호용), 자기질타일 (90mm)
3146194 | 170 | 29 | 지상 1층 | -510 | 바닥 : A1-14-03A-시멘트모르타르(고름용), 도막방수, 시멘트모르타르(보호용), 자기질타일 (90mm)
3146199 | 171 | 34 | 지상 1층 | -510 | 바닥 : A1-14-03A-시멘트모르타르(고름용), 도막방수, 시멘트모르타르(보호용), 자기질타일 (90mm)
3146258 | 203 | 48 | 지상 3층 | 0 | 레벨 : 지상 3층
3146317 | 221 | 75 | 지상 4층 | 0 | 레벨 : 지상 4층
3146376 | 226 | 89 | 지상 5층 | 0 | 레벨 : 지상 5층
3146435 | 241 | 103 | 지상 6층 | 0 | 레벨 : 지상 6층
3146494 | 267 | 117 | 지상 7층 | 0 | 레벨 : 지상 7층
3146553 | 279 | 131 | 지상 8층 | 0 | 레벨 : 지상 8층
3146612 | 298 | 145 | 지상 9층 | 0 | 레벨 : 지상 9층
3146671 | 313 | 159 | 지상 10층 | 0 | 레벨 : 지상 10층
7700643 | 171 | 168 | 지상 1층 | -510 | 바닥 : A1-14-03A-시멘트모르타르(고름용), 도막방수, 시멘트모르타르(보호용), 자기질타일 (90mm)
7705758 | 188 | 169 | 지상 2층 | 40 | 바닥 : A1-14-03A-시멘트모르타르(고름용), 도막방수, 시멘트모르타르(보호용), 자기질타일 (90mm)
7705759 | 188 | 170 | 지상 2층 | 40 | 바닥 : A1-14-03A-시멘트모르타르(고름용), 도막방수, 시멘트모르타르(보호용), 자기질타일 (90mm)
7706115 | 202 | 171 | 지상 3층 | 40 | 바닥 : A1-14-03A-시멘트모르타르(고름용), 도막방수, 시멘트모르타르(보호용), 자기질타일 (90mm)
7706116 | 202 | 172 | 지상 3층 | 40 | 바닥 : A1-14-03A-시멘트모르타르(고름용), 도막방수, 시멘트모르타르(보호용), 자기질타일 (90mm)
7706172 | 222 | 173 | 지상 4층 | 40 | 바닥 : A1-14-03A-시멘트모르타르(고름용), 도막방수, 시멘트모르타르(보호용), 자기질타일 (90mm)
7706173 | 222 | 174 | 지상 4층 | 40 | 바닥 : A1-14-03A-시멘트모르타르(고름용), 도막방수, 시멘트모르타르(보호용), 자기질타일 (90mm)
7706229 | 225 | 175 | 지상 5층 | 40 | 바닥 : A1-14-03A-시멘트모르타르(고름용), 도막방수, 시멘트모르타르(보호용), 자기질타일 (90mm)
7706230 | 225 | 176 | 지상 5층 | 40 | 바닥 : A1-14-03A-시멘트모르타르(고름용), 도막방수, 시멘트모르타르(보호용), 자기질타일 (90mm)
7706286 | 240 | 177 | 지상 6층 | 40 | 바닥 : A1-14-03A-시멘트모르타르(고름용), 도막방수, 시멘트모르타르(보호용), 자기질타일 (90mm)
7706287 | 240 | 178 | 지상 6층 | 40 | 바닥 : A1-14-03A-시멘트모르타르(고름용), 도막방수, 시멘트모르타르(보호용), 자기질타일 (90mm)
7706343 | 266 | 179 | 지상 7층 | 40 | 바닥 : A1-14-03A-시멘트모르타르(고름용), 도막방수, 시멘트모르타르(보호용), 자기질타일 (90mm)
7706344 | 266 | 180 | 지상 7층 | 40 | 바닥 : A1-14-03A-시멘트모르타르(고름용), 도막방수, 시멘트모르타르(보호용), 자기질타일 (90mm)
7706400 | 278 | 181 | 지상 8층 | 40 | 바닥 : A1-14-03A-시멘트모르타르(고름용), 도막방수, 시멘트모르타르(보호용), 자기질타일 (90mm)
7706401 | 278 | 182 | 지상 8층 | 40 | 바닥 : A1-14-03A-시멘트모르타르(고름용), 도막방수, 시멘트모르타르(보호용), 자기질타일 (90mm)
7706457 | 297 | 183 | 지상 9층 | 40 | 바닥 : A1-14-03A-시멘트모르타르(고름용), 도막방수, 시멘트모르타르(보호용), 자기질타일 (90mm)
7706458 | 297 | 184 | 지상 9층 | 40 | 바닥 : A1-14-03A-시멘트모르타르(고름용), 도막방수, 시멘트모르타르(보호용), 자기질타일 (90mm)
7706514 | 312 | 185 | 지상 10층 | 0 | 레벨 : 지상 10층
7706515 | 312 | 186 | 지상 10층 | 0 | 레벨 : 지상 10층
7707631 | 189 | 187 | 지상 2층 | 40 | 바닥 : A1-14-03A-시멘트모르타르(고름용), 도막방수, 시멘트모르타르(보호용), 자기질타일 (90mm)
7707855 | 203 | 188 | 지상 3층 | 40 | 바닥 : A1-14-03A-시멘트모르타르(고름용), 도막방수, 시멘트모르타르(보호용), 자기질타일 (90mm)
7707896 | 221 | 189 | 지상 4층 | 40 | 바닥 : A1-14-03A-시멘트모르타르(고름용), 도막방수, 시멘트모르타르(보호용), 자기질타일 (90mm)
7707937 | 226 | 190 | 지상 5층 | 40 | 바닥 : A1-14-03A-시멘트모르타르(고름용), 도막방수, 시멘트모르타르(보호용), 자기질타일 (90mm)
7707978 | 241 | 191 | 지상 6층 | 40 | 바닥 : A1-14-03A-시멘트모르타르(고름용), 도막방수, 시멘트모르타르(보호용), 자기질타일 (90mm)
7708019 | 267 | 192 | 지상 7층 | 40 | 바닥 : A1-14-03A-시멘트모르타르(고름용), 도막방수, 시멘트모르타르(보호용), 자기질타일 (90mm)
7708060 | 279 | 193 | 지상 8층 | 40 | 바닥 : A1-14-03A-시멘트모르타르(고름용), 도막방수, 시멘트모르타르(보호용), 자기질타일 (90mm)
7708101 | 298 | 194 | 지상 9층 | 40 | 바닥 : A1-14-03A-시멘트모르타르(고름용), 도막방수, 시멘트모르타르(보호용), 자기질타일 (90mm)
7708142 | 313 | 195 | 지상 10층 | 0 | 레벨 : 지상 10층

# IfcFurnishingElement: PF531-거울:PF531-거울 600x800 (3)
Type - Material: KBIMS-거울
Type - ID 데이터 - OmniClass 번호: 23.75.00.00; OmniClass 제목: Climate Control (HVAC); 단가: 0; 유형 이름: PF531-거울 600x800
Type - 구속조건 - 기본 높이: 0 mm
Type - 기타 - 카테고리: 가구; KBIMS-부위코드: E71320; 제작정보: AIBIM-2023; 조달청표준공사코드: HB3; 패밀리 이름: PF531-거울
Type - 치수 - 가로: 600 mm; 높이: 800 mm; 세로: 10 mm
Pset_QuantityTakeOff - Reference: PF531-거울 600x800
공정 - 생성 공정: 새 구성
구속조건 - 레벨: 지상 3층; 가까운 요소로 이동: no; 레벨로부터의 높이: 1000 mm; 호스트: 레벨 : 지상 3층; 호스트에서의 간격띄우기: 1000 mm
기타 - 패밀리: PF531-거울; 유형: PF531-거울 600x800; 유형 ID: 6405131; 패밀리 및 유형: PF531-거울: PF531-거울 600x800
치수 - 면적: 0.494 m2; 체적: 0.0048 m3
Name (PF531-거울:PF531-거울 600x800:...) | In
3239075 | 지상 3층
3239107 | 지상 3층
3239115 | 202

# IfcFurnishingElement: PF531-거울:PF531-거울 800x800 (20)
Type - Material: KBIMS-거울
Type - ID 데이터 - OmniClass 번호: 23.75.00.00; OmniClass 제목: Climate Control (HVAC); 단가: 0; 유형 이름: PF531-거울 800x800
Type - 구속조건 - 기본 높이: 0 mm
Type - 기타 - 카테고리: 가구; KBIMS-부위코드: E71320; 제작정보: AIBIM-2023; 조달청표준공사코드: HB3; 패밀리 이름: PF531-거울
Type - 치수 - 가로: 800 mm; 높이: 800 mm; 세로: 10 mm
Pset_QuantityTakeOff - Reference: PF531-거울 800x800
공정 - 생성 공정: 새 구성
구속조건 - 가까운 요소로 이동: no; 호스트에서의 간격띄우기: 1000 mm
기타 - 유형: PF531-거울 800x800; 유형 ID: 6405129; 패밀리: PF531-거울; 패밀리 및 유형: PF531-거울: PF531-거울 800x800
치수 - 면적: 0.656 m2; 체적: 0.0064 m3
Name (PF531-거울:PF531-거울 800x800:...) | In | 레벨 | 레벨로부터의 높이 (mm) | 호스트
3145955 | 188 | 지상 2층 | 1000 | 레벨 : 지상 2층
3145961 | 189 | 지상 2층 | 1000 | 레벨 : 지상 2층
3146209 | 170 | 지상 1층 | 490 | 바닥 : A1-14-03A-시멘트모르타르(고름용), 도막방수, 시멘트모르타르(보호용), 자기질타일 (90mm)
3146215 | 171 | 지상 1층 | 490 | 바닥 : A1-14-03A-시멘트모르타르(고름용), 도막방수, 시멘트모르타르(보호용), 자기질타일 (90mm)
3146268 | 202 | 지상 3층 | 1000 | 레벨 : 지상 3층
3146274 | 203 | 지상 3층 | 1000 | 레벨 : 지상 3층
3146327 | 222 | 지상 4층 | 1000 | 레벨 : 지상 4층
3146333 | 221 | 지상 4층 | 1000 | 레벨 : 지상 4층
3146386 | 225 | 지상 5층 | 1000 | 레벨 : 지상 5층
3146392 | 226 | 지상 5층 | 1000 | 레벨 : 지상 5층
3146445 | 240 | 지상 6층 | 1000 | 레벨 : 지상 6층
3146451 | 241 | 지상 6층 | 1000 | 레벨 : 지상 6층
3146504 | 266 | 지상 7층 | 1000 | 레벨 : 지상 7층
3146510 | 267 | 지상 7층 | 1000 | 레벨 : 지상 7층
3146563 | 278 | 지상 8층 | 1000 | 레벨 : 지상 8층
3146569 | 279 | 지상 8층 | 1000 | 레벨 : 지상 8층
3146622 | 297 | 지상 9층 | 1000 | 레벨 : 지상 9층
3146628 | 298 | 지상 9층 | 1000 | 레벨 : 지상 9층
3146681 | 312 | 지상 10층 | 1000 | 레벨 : 지상 10층
3146687 | 313 | 지상 10층 | 1000 | 레벨 : 지상 10층

# IfcFurnishingElement: PF581-대변기 칸막이:PF581-대변기 칸막이(오른쪽) 1300x950x1900, PF581-대변기 칸막이:PF581-대변기 칸막이(오른쪽) 1300x950x1900:3146213
In: 171
Type - Material: <Unnamed> (6), KBIMS-스테인리스 스틸_도금 (8), KBIMS-이동식칸막이 (4)
Type - ID 데이터 - OmniClass 번호: 23.75.00.00; OmniClass 제목: Climate Control (HVAC); 단가: 0; 유형 이름: PF581-대변기 칸막이(오른쪽) 1300x950x1900
Type - 구속조건 - 기본 높이: 0 mm
Type - 그래픽 - 큐비클 다리: yes; 큐비클_좌: no; 큐비클_우: yes
Type - 기타 - 카테고리: 가구; KBIMS-부위코드: E714; 제작정보: AIBIM-2023; 조달청표준공사코드: AOC771; 패밀리 이름: PF581-대변기 칸막이
Type - 재료 및 마감재 - 출입문 재료: KBIMS-이동식칸막이; 큐비클다리 재료: KBIMS-스테인리스 스틸_도금; 큐비클 재료: KBIMS-이동식칸막이
Type - 치수 - 가로: 1300 mm; 깊이: 950 mm; 높이: 1900 mm; 높이_출입문: 1800 mm; 두께: 40 mm; 폭_우: 50 mm; 폭_좌: 650 mm; 폭_출입문: 600 mm; 하단 간격띄우기: 100 mm
Pset_QuantityTakeOff - Reference: PF581-대변기 칸막이(오른쪽) 1300x950x1900
공정 - 생성 공정: 새 구성
구속조건 - 레벨: 지상 1층; 가까운 요소로 이동: no; 호스트에서의 간격띄우기: 0 mm; 레벨로부터의 높이: -510 mm; 호스트: 바닥 : A1-14-03A-시멘트모르타르(고름용), 도막방수, 시멘트모르타르(보호용), 자기질타일 (90mm)
기타 - 패밀리: PF581-대변기 칸막이; 유형: PF581-대변기 칸막이(오른쪽) 1300x950x1900; 유형 ID: 6868565; 패밀리 및 유형: PF581-대변기 칸막이: PF581-대변기 칸막이(오른쪽) 1300x950x1900
치수 - 면적: 6.10688 m2; 체적: 0.217512 m3

# IfcFurnishingElement: PF581-대변기 칸막이:PF581-대변기 칸막이(오른쪽) 1300x950x2400 (8)
Type - Material: <Unnamed> (6), KBIMS-스테인리스 스틸_도금 (8), KBIMS-이동식칸막이 (4)
Type - ID 데이터 - OmniClass 번호: 23.75.00.00; OmniClass 제목: Climate Control (HVAC); 단가: 0; 유형 이름: PF581-대변기 칸막이(오른쪽) 1300x950x2400
Type - 구속조건 - 기본 높이: 0 mm
Type - 그래픽 - 큐비클 다리: yes; 큐비클_좌: no; 큐비클_우: yes
Type - 기타 - 카테고리: 가구; KBIMS-부위코드: E714; 제작정보: AIBIM-2023; 조달청표준공사코드: AOC771; 패밀리 이름: PF581-대변기 칸막이
Type - 재료 및 마감재 - 출입문 재료: KBIMS-이동식칸막이; 큐비클다리 재료: KBIMS-스테인리스 스틸_도금; 큐비클 재료: KBIMS-이동식칸막이
Type - 치수 - 가로: 1300 mm; 깊이: 950 mm; 높이: 2400 mm; 높이_출입문: 1900 mm; 두께: 40 mm; 폭_우: 50 mm; 폭_좌: 650 mm; 폭_출입문: 600 mm; 하단 간격띄우기: 100 mm
Pset_QuantityTakeOff - Reference: PF581-대변기 칸막이(오른쪽) 1300x950x2400
공정 - 생성 공정: 새 구성
구속조건 - 가까운 요소로 이동: no; 레벨로부터의 높이: 0 mm; 호스트에서의 간격띄우기: 0 mm
기타 - 패밀리: PF581-대변기 칸막이; 유형: PF581-대변기 칸막이(오른쪽) 1300x950x2400; 유형 ID: 6868567; 패밀리 및 유형: PF581-대변기 칸막이: PF581-대변기 칸막이(오른쪽) 1300x950x2400
치수 - 면적: 7.53028 m2; 체적: 0.270782 m3
Name (PF581-대변기 칸막이:PF581-대변기 칸막이(오른쪽) 1300x950x2400:...) | In | 레벨 | 호스트 | Material
3146272 | 203 | 지상 3층 | 레벨 : 지상 3층
3146331 | 221 | 지상 4층 | 레벨 : 지상 4층 | <Unnamed>, KBIMS-스테인리스 스틸_도금, KBIMS-이동식칸막이
3146390 | 226 | 지상 5층 | 레벨 : 지상 5층 | <Unnamed>, KBIMS-스테인리스 스틸_도금, KBIMS-이동식칸막이
3146449 | 241 | 지상 6층 | 레벨 : 지상 6층 | <Unnamed>, KBIMS-스테인리스 스틸_도금, KBIMS-이동식칸막이
3146508 | 267 | 지상 7층 | 레벨 : 지상 7층 | <Unnamed>, KBIMS-스테인리스 스틸_도금, KBIMS-이동식칸막이
3146567 | 279 | 지상 8층 | 레벨 : 지상 8층 | <Unnamed>, KBIMS-스테인리스 스틸_도금, KBIMS-이동식칸막이
3146626 | 298 | 지상 9층 | 레벨 : 지상 9층 | <Unnamed>, KBIMS-스테인리스 스틸_도금, KBIMS-이동식칸막이
3146685 | 313 | 지상 10층 | 레벨 : 지상 10층 | <Unnamed>, KBIMS-스테인리스 스틸_도금, KBIMS-이동식칸막이

# IfcFurnishingElement: PF581-대변기 칸막이:PF581-대변기 칸막이(왼쪽) 970x1430x1900 (2)
In: 170
Type - Material: <Unnamed> (6), KBIMS-스테인리스 스틸_도금 (8), KBIMS-이동식칸막이 (4)
Type - ID 데이터 - OmniClass 번호: 23.75.00.00; OmniClass 제목: Climate Control (HVAC); 단가: 0; 유형 이름: PF581-대변기 칸막이(왼쪽) 970x1430x1900
Type - 구속조건 - 기본 높이: 0 mm
Type - 그래픽 - 큐비클_우: no; 큐비클_좌: yes; 큐비클 다리: yes
Type - 기타 - 카테고리: 가구; KBIMS-부위코드: E714; 제작정보: AIBIM-2023; 조달청표준공사코드: AOC771; 패밀리 이름: PF581-대변기 칸막이
Type - 재료 및 마감재 - 출입문 재료: KBIMS-이동식칸막이; 큐비클다리 재료: KBIMS-스테인리스 스틸_도금; 큐비클 재료: KBIMS-이동식칸막이
Type - 치수 - 가로: 970 mm; 깊이: 1430 mm; 높이: 1900 mm; 높이_출입문: 1800 mm; 두께: 40 mm; 폭_우: 185 mm; 폭_좌: 185 mm; 폭_출입문: 600 mm; 하단 간격띄우기: 100 mm
Pset_QuantityTakeOff - Reference: PF581-대변기 칸막이(왼쪽) 970x1430x1900
공정 - 생성 공정: 새 구성
구속조건 - 레벨: 지상 1층; 가까운 요소로 이동: no; 호스트에서의 간격띄우기: 0 mm; 레벨로부터의 높이: -510 mm; 호스트: 바닥 : A1-14-03A-시멘트모르타르(고름용), 도막방수, 시멘트모르타르(보호용), 자기질타일 (90mm)
기타 - 패밀리: PF581-대변기 칸막이; 유형: PF581-대변기 칸막이(왼쪽) 970x1430x1900; 유형 ID: 6868569; 패밀리 및 유형: PF581-대변기 칸막이: PF581-대변기 칸막이(왼쪽) 970x1430x1900
치수 - 면적: 7.26608 m2; 체적: 0.262872 m3
Name (PF581-대변기 칸막이:PF581-대변기 칸막이(왼쪽) 970x1430x1900:...)
3146202
3146204 | Material: <Unnamed>, KBIMS-스테인리스 스틸_도금, KBIMS-이동식칸막이

# IfcFurnishingElement: PF581-대변기 칸막이:PF581-대변기 칸막이(왼쪽) 970x1430x2400 (18)
Type - Material: <Unnamed> (6), KBIMS-스테인리스 스틸_도금 (8), KBIMS-이동식칸막이 (4)
Type - ID 데이터 - OmniClass 번호: 23.75.00.00; OmniClass 제목: Climate Control (HVAC); 단가: 0; 유형 이름: PF581-대변기 칸막이(왼쪽) 970x1430x2400
Type - 구속조건 - 기본 높이: 0 mm
Type - 그래픽 - 큐비클_우: no; 큐비클_좌: yes; 큐비클 다리: yes
Type - 기타 - 카테고리: 가구; KBIMS-부위코드: E714; 제작정보: AIBIM-2023; 조달청표준공사코드: AOC771; 패밀리 이름: PF581-대변기 칸막이
Type - 재료 및 마감재 - 출입문 재료: KBIMS-이동식칸막이; 큐비클다리 재료: KBIMS-스테인리스 스틸_도금; 큐비클 재료: KBIMS-이동식칸막이
Type - 치수 - 가로: 970 mm; 깊이: 1430 mm; 높이: 2400 mm; 높이_출입문: 1900 mm; 두께: 40 mm; 폭_우: 185 mm; 폭_좌: 185 mm; 폭_출입문: 600 mm; 하단 간격띄우기: 100 mm
Pset_QuantityTakeOff - Reference: PF581-대변기 칸막이(왼쪽) 970x1430x2400
공정 - 생성 공정: 새 구성
구속조건 - 가까운 요소로 이동: no; 레벨로부터의 높이: 0 mm; 호스트에서의 간격띄우기: 0 mm
기타 - 유형: PF581-대변기 칸막이(왼쪽) 970x1430x2400; 유형 ID: 6868571; 패밀리: PF581-대변기 칸막이; 패밀리 및 유형: PF581-대변기 칸막이: PF581-대변기 칸막이(왼쪽) 970x1430x2400
치수 - 면적: 9.00448 m2; 체적: 0.328742 m3
Name (PF581-대변기 칸막이:PF581-대변기 칸막이(왼쪽) 970x1430x2400:...) | In | 레벨 | 호스트 | Material
3145948 | 188 | 지상 2층 | 레벨 : 지상 2층
3145950 | 188 | 지상 2층 | 레벨 : 지상 2층 | <Unnamed>, KBIMS-스테인리스 스틸_도금, KBIMS-이동식칸막이
3146261 | 202 | 지상 3층 | 레벨 : 지상 3층 | <Unnamed>, KBIMS-스테인리스 스틸_도금, KBIMS-이동식칸막이
3146263 | 202 | 지상 3층 | 레벨 : 지상 3층 | <Unnamed>, KBIMS-스테인리스 스틸_도금, KBIMS-이동식칸막이
3146320 | 222 | 지상 4층 | 레벨 : 지상 4층 | <Unnamed>, KBIMS-스테인리스 스틸_도금, KBIMS-이동식칸막이
3146322 | 222 | 지상 4층 | 레벨 : 지상 4층 | <Unnamed>, KBIMS-스테인리스 스틸_도금, KBIMS-이동식칸막이
3146379 | 225 | 지상 5층 | 레벨 : 지상 5층 | <Unnamed>, KBIMS-스테인리스 스틸_도금, KBIMS-이동식칸막이
3146381 | 225 | 지상 5층 | 레벨 : 지상 5층 | <Unnamed>, KBIMS-스테인리스 스틸_도금, KBIMS-이동식칸막이
3146438 | 240 | 지상 6층 | 레벨 : 지상 6층 | <Unnamed>, KBIMS-스테인리스 스틸_도금, KBIMS-이동식칸막이
3146440 | 240 | 지상 6층 | 레벨 : 지상 6층 | <Unnamed>, KBIMS-스테인리스 스틸_도금, KBIMS-이동식칸막이
3146497 | 266 | 지상 7층 | 레벨 : 지상 7층 | <Unnamed>, KBIMS-스테인리스 스틸_도금, KBIMS-이동식칸막이
3146499 | 266 | 지상 7층 | 레벨 : 지상 7층 | <Unnamed>, KBIMS-스테인리스 스틸_도금, KBIMS-이동식칸막이
3146556 | 278 | 지상 8층 | 레벨 : 지상 8층 | <Unnamed>, KBIMS-스테인리스 스틸_도금, KBIMS-이동식칸막이
3146558 | 278 | 지상 8층 | 레벨 : 지상 8층 | <Unnamed>, KBIMS-스테인리스 스틸_도금, KBIMS-이동식칸막이
3146615 | 297 | 지상 9층 | 레벨 : 지상 9층 | <Unnamed>, KBIMS-스테인리스 스틸_도금, KBIMS-이동식칸막이
3146617 | 297 | 지상 9층 | 레벨 : 지상 9층 | <Unnamed>, KBIMS-스테인리스 스틸_도금, KBIMS-이동식칸막이
3146674 | 312 | 지상 10층 | 레벨 : 지상 10층 | <Unnamed>, KBIMS-스테인리스 스틸_도금, KBIMS-이동식칸막이
3146676 | 312 | 지상 10층 | 레벨 : 지상 10층 | <Unnamed>, KBIMS-스테인리스 스틸_도금, KBIMS-이동식칸막이

# IfcFurnishingElement: PF581-대변기 칸막이:PF581-대변기 칸막이(출입면) 970x1430x1900, PF581-대변기 칸막이:PF581-대변기 칸막이(출입면) 970x1430x1900:3146203
In: 170
Type - Material: <Unnamed> (6), KBIMS-스테인리스 스틸_도금 (4), KBIMS-이동식칸막이 (3)
Type - ID 데이터 - OmniClass 번호: 23.75.00.00; OmniClass 제목: Climate Control (HVAC); 단가: 0; 유형 이름: PF581-대변기 칸막이(출입면) 970x1430x1900
Type - 구속조건 - 기본 높이: 0 mm
Type - 그래픽 - 큐비클_우: no; 큐비클 다리: yes; 큐비클_좌: no
Type - 기타 - 카테고리: 가구; KBIMS-부위코드: E714; 제작정보: AIBIM-2023; 조달청표준공사코드: AOC771; 패밀리 이름: PF581-대변기 칸막이
Type - 재료 및 마감재 - 출입문 재료: KBIMS-이동식칸막이; 큐비클다리 재료: KBIMS-스테인리스 스틸_도금; 큐비클 재료: KBIMS-이동식칸막이
Type - 치수 - 가로: 970 mm; 깊이: 1430 mm; 높이: 1900 mm; 높이_출입문: 1800 mm; 두께: 40 mm; 폭_우: 185 mm; 폭_좌: 185 mm; 폭_출입문: 600 mm; 하단 간격띄우기: 100 mm
Pset_QuantityTakeOff - Reference: PF581-대변기 칸막이(출입면) 970x1430x1900
공정 - 생성 공정: 새 구성
구속조건 - 레벨: 지상 1층; 가까운 요소로 이동: no; 호스트에서의 간격띄우기: 0 mm; 레벨로부터의 높이: -510 mm; 호스트: 바닥 : A1-14-03A-시멘트모르타르(고름용), 도막방수, 시멘트모르타르(보호용), 자기질타일 (90mm)
기타 - 패밀리: PF581-대변기 칸막이; 유형: PF581-대변기 칸막이(출입면) 970x1430x1900; 유형 ID: 6868573; 패밀리 및 유형: PF581-대변기 칸막이: PF581-대변기 칸막이(출입면) 970x1430x1900
치수 - 면적: 7.26608 m2; 체적: 0.262872 m3

# IfcFurnishingElement: PF581-대변기 칸막이:PF581-대변기 칸막이(출입면) 970x1430x2400 (9)
Type - Material: <Unnamed> (6), KBIMS-스테인리스 스틸_도금 (4), KBIMS-이동식칸막이 (3)
Type - ID 데이터 - OmniClass 번호: 23.75.00.00; OmniClass 제목: Climate Control (HVAC); 단가: 0; 유형 이름: PF581-대변기 칸막이(출입면) 970x1430x2400
Type - 구속조건 - 기본 높이: 0 mm
Type - 그래픽 - 큐비클_우: no; 큐비클 다리: yes; 큐비클_좌: no
Type - 기타 - 카테고리: 가구; KBIMS-부위코드: E714; 제작정보: AIBIM-2023; 조달청표준공사코드: AOC771; 패밀리 이름: PF581-대변기 칸막이
Type - 재료 및 마감재 - 출입문 재료: KBIMS-이동식칸막이; 큐비클다리 재료: KBIMS-스테인리스 스틸_도금; 큐비클 재료: KBIMS-이동식칸막이
Type - 치수 - 가로: 970 mm; 깊이: 1430 mm; 높이: 2400 mm; 높이_출입문: 1900 mm; 두께: 40 mm; 폭_우: 185 mm; 폭_좌: 185 mm; 폭_출입문: 600 mm; 하단 간격띄우기: 100 mm
Pset_QuantityTakeOff - Reference: PF581-대변기 칸막이(출입면) 970x1430x2400
공정 - 생성 공정: 새 구성
구속조건 - 가까운 요소로 이동: no; 레벨로부터의 높이: 0 mm; 호스트에서의 간격띄우기: 0 mm
기타 - 패밀리: PF581-대변기 칸막이; 유형: PF581-대변기 칸막이(출입면) 970x1430x2400; 유형 ID: 6868575; 패밀리 및 유형: PF581-대변기 칸막이: PF581-대변기 칸막이(출입면) 970x1430x2400
치수 - 면적: 9.00448 m2; 체적: 0.328742 m3
Name (PF581-대변기 칸막이:PF581-대변기 칸막이(출입면) 970x1430x2400:...) | In | 레벨 | 호스트 | Material
3145949 | 188 | 지상 2층 | 레벨 : 지상 2층
3146262 | 202 | 지상 3층 | 레벨 : 지상 3층 | <Unnamed>, KBIMS-스테인리스 스틸_도금, KBIMS-이동식칸막이
3146321 | 222 | 지상 4층 | 레벨 : 지상 4층 | <Unnamed>, KBIMS-스테인리스 스틸_도금, KBIMS-이동식칸막이
3146380 | 225 | 지상 5층 | 레벨 : 지상 5층 | <Unnamed>, KBIMS-스테인리스 스틸_도금, KBIMS-이동식칸막이
3146439 | 240 | 지상 6층 | 레벨 : 지상 6층 | <Unnamed>, KBIMS-스테인리스 스틸_도금, KBIMS-이동식칸막이
3146498 | 266 | 지상 7층 | 레벨 : 지상 7층 | <Unnamed>, KBIMS-스테인리스 스틸_도금, KBIMS-이동식칸막이
3146557 | 278 | 지상 8층 | 레벨 : 지상 8층 | <Unnamed>, KBIMS-스테인리스 스틸_도금, KBIMS-이동식칸막이
3146616 | 297 | 지상 9층 | 레벨 : 지상 9층 | <Unnamed>, KBIMS-스테인리스 스틸_도금, KBIMS-이동식칸막이
3146675 | 312 | 지상 10층 | 레벨 : 지상 10층 | <Unnamed>, KBIMS-스테인리스 스틸_도금, KBIMS-이동식칸막이

# IfcFurnishingElement: PF581-대변기 칸막이:PF581-대변기부스, PF581-대변기 칸막이:PF581-대변기부스:8036871
In: 189
Type - Material: <Unnamed> (6), KBIMS-스테인리스 스틸_도금 (12), KBIMS-이동식칸막이 (5)
Type - ID 데이터 - OmniClass 번호: 23.75.00.00; OmniClass 제목: Climate Control (HVAC); 단가: 0; 유형 이름: PF581-대변기부스
Type - 구속조건 - 기본 높이: 0 mm
Type - 그래픽 - 큐비클_좌: yes; 큐비클 다리: yes; 큐비클_우: yes
Type - 기타 - 카테고리: 가구; KBIMS-부위코드: E71410; 제작정보: bSK-2021_KBIMS2.0-bC; 조달청표준공사코드: AOC771; 패밀리 이름: PF581-대변기 칸막이
Type - 재료 및 마감재 - 출입문 재료: KBIMS-이동식칸막이; 큐비클다리 재료: KBIMS-스테인리스 스틸_도금; 큐비클 재료: KBIMS-이동식칸막이
Type - 치수 - 가로: 1300 mm; 깊이: 1300 mm; 높이: 2400 mm; 높이_출입문: 1900 mm; 두께: 30 mm; 폭_우: 350 mm; 폭_좌: 350 mm; 폭_출입문: 600 mm; 하단 간격띄우기: 100 mm
Pset_QuantityTakeOff - Reference: PF581-대변기부스
공정 - 생성 공정: 새 구성
구속조건 - 레벨: 지상 2층; 가까운 요소로 이동: no; 호스트에서의 간격띄우기: 0 mm; 레벨로부터의 높이: 40 mm; 호스트: 바닥 : A1-14-03A-시멘트모르타르(고름용), 도막방수, 시멘트모르타르(보호용), 자기질타일 (90mm)
기타 - 패밀리: PF581-대변기 칸막이; 유형: PF581-대변기부스; 유형 ID: 8037256; 패밀리 및 유형: PF581-대변기 칸막이: PF581-대변기부스
치수 - 면적: 9.06458 m2; 체적: 0.251443 m3

# IfcFurnishingElement: PF582-소변기 칸막이:PF582-소변기 칸막이 (19)
Type - Material: KBIMS-스테인리스 스틸_도금 (2), KBIMS-이동식칸막이
Type - ID 데이터 - OmniClass 번호: 23.75.00.00; OmniClass 제목: Climate Control (HVAC); 단가: 0; 유형 이름: PF582-소변기 칸막이
Type - 구속조건 - 기본 높이: 0 mm
Type - 그래픽 - 큐비클 다리: yes
Type - 기타 - 카테고리: 가구; KBIMS-부위코드: E714; 제작정보: AIBIM-2023; 조달청표준공사코드: AOC771; 패밀리 이름: PF582-소변기 칸막이
Type - 재료 및 마감재 - 큐비클다리 재료: KBIMS-스테인리스 스틸_도금
Type - 치수 - 가로: 40 mm; 깊이: 450 mm; 높이: 1200 mm; 하단 간격띄우기: 150 mm
Pset_QuantityTakeOff - Reference: PF582-소변기 칸막이
공정 - 생성 공정: 새 구성
구속조건 - 가까운 요소로 이동: no; 호스트에서의 간격띄우기: 0 mm
기타 - 유형: PF582-소변기 칸막이; 유형 ID: 6404124; 패밀리: PF582-소변기 칸막이; 패밀리 및 유형: PF582-소변기 칸막이: PF582-소변기 칸막이
치수 - 면적: 0.539183 m2; 체적: 0.0188449 m3
Name (PF582-소변기 칸막이:PF582-소변기 칸막이:...) | In | 레벨 | 레벨로부터의 높이 (mm) | 호스트 | Material
3145957 | 189 | 지상 2층 | 0 | 레벨 : 지상 2층
3145958 | 189 | 지상 2층 | 0 | 레벨 : 지상 2층 | KBIMS-스테인리스 스틸_도금, KBIMS-이동식칸막이
3146211 | 171 | 지상 1층 | -510 | 바닥 : A1-14-03A-시멘트모르타르(고름용), 도막방수, 시멘트모르타르(보호용), 자기질타일 (90mm) | KBIMS-스테인리스 스틸_도금, KBIMS-이동식칸막이
3146212 | 171 | 지상 1층 | -510 | 바닥 : A1-14-03A-시멘트모르타르(고름용), 도막방수, 시멘트모르타르(보호용), 자기질타일 (90mm) | KBIMS-스테인리스 스틸_도금, KBIMS-이동식칸막이
3146270 | 203 | 지상 3층 | 0 | 레벨 : 지상 3층 | KBIMS-스테인리스 스틸_도금, KBIMS-이동식칸막이
3146329 | 221 | 지상 4층 | 0 | 레벨 : 지상 4층 | KBIMS-스테인리스 스틸_도금, KBIMS-이동식칸막이
3146330 | 221 | 지상 4층 | 0 | 레벨 : 지상 4층 | KBIMS-스테인리스 스틸_도금, KBIMS-이동식칸막이
3146388 | 226 | 지상 5층 | 0 | 레벨 : 지상 5층 | KBIMS-스테인리스 스틸_도금, KBIMS-이동식칸막이
3146389 | 226 | 지상 5층 | 0 | 레벨 : 지상 5층 | KBIMS-스테인리스 스틸_도금, KBIMS-이동식칸막이
3146447 | 241 | 지상 6층 | 0 | 레벨 : 지상 6층 | KBIMS-스테인리스 스틸_도금, KBIMS-이동식칸막이
3146448 | 241 | 지상 6층 | 0 | 레벨 : 지상 6층 | KBIMS-스테인리스 스틸_도금, KBIMS-이동식칸막이
3146506 | 267 | 지상 7층 | 0 | 레벨 : 지상 7층 | KBIMS-스테인리스 스틸_도금, KBIMS-이동식칸막이
3146507 | 267 | 지상 7층 | 0 | 레벨 : 지상 7층 | KBIMS-스테인리스 스틸_도금, KBIMS-이동식칸막이
3146565 | 279 | 지상 8층 | 0 | 레벨 : 지상 8층 | KBIMS-스테인리스 스틸_도금, KBIMS-이동식칸막이
3146566 | 279 | 지상 8층 | 0 | 레벨 : 지상 8층 | KBIMS-스테인리스 스틸_도금, KBIMS-이동식칸막이
3146624 | 298 | 지상 9층 | 0 | 레벨 : 지상 9층 | KBIMS-스테인리스 스틸_도금, KBIMS-이동식칸막이
3146625 | 298 | 지상 9층 | 0 | 레벨 : 지상 9층 | KBIMS-스테인리스 스틸_도금, KBIMS-이동식칸막이
3146683 | 313 | 지상 10층 | 0 | 레벨 : 지상 10층 | KBIMS-스테인리스 스틸_도금, KBIMS-이동식칸막이
3146684 | 313 | 지상 10층 | 0 | 레벨 : 지상 10층 | KBIMS-스테인리스 스틸_도금, KBIMS-이동식칸막이

# IfcFurnishingElement: PF591-대변기용 장애인 손잡이(T자 고정식):PF591-대변기용 장애인 손잡이(T자 고정식) (20)
Type - Material: KBIMS-스테인리스 스틸_도금 (3)
Type - ID 데이터 - OmniClass 번호: 23.75.00.00; OmniClass 제목: Climate Control (HVAC); 단가: 0; 유형 이름: PF591-대변기용 장애인 손잡이(T자 고정식)
Type - 구속조건 - 기본 높이: 0 mm
Type - 기타 - 카테고리: 가구; KBIMS-부위코드: E713; 제작정보: AIBIM-2023; 조달청표준공사코드: APA18; 패밀리 이름: PF591-대변기용 장애인 손잡이(T자 고정식)
Type - 치수 - 가로: 550 mm; 높이: 700 mm; 세로: 200 mm
Pset_QuantityTakeOff - Reference: PF591-대변기용 장애인 손잡이(T자 고정식)
공정 - 생성 공정: 새 구성
구속조건 - 가까운 요소로 이동: no; 호스트에서의 간격띄우기: 0 mm
기타 - 유형: PF591-대변기용 장애인 손잡이(T자 고정식); 유형 ID: 6419429; 패밀리: PF591-대변기용 장애인 손잡이(T자 고정식); 패밀리 및 유형: PF591-대변기용 장애인 손잡이(T자 고정식): PF591-대변기용 장애인 손잡이(T자 고정식)
치수 - 면적: 0.0881554 m2; 체적: 0.00143236 m3
Name (PF591-대변기용 장애인 손잡이(T자 고정식):PF591-대변기용 장애인 손잡이(T자 고정식):...) | In | 레벨 | 레벨로부터의 높이 (mm) | 호스트 | Material
3145963 | 188 | 지상 2층 | 0 | 레벨 : 지상 2층
3145965 | 189 | 지상 2층 | 0 | 레벨 : 지상 2층 | KBIMS-스테인리스 스틸_도금
3146217 | 170 | 지상 1층 | -510 | 바닥 : A1-14-03A-시멘트모르타르(고름용), 도막방수, 시멘트모르타르(보호용), 자기질타일 (90mm) | KBIMS-스테인리스 스틸_도금
3146219 | 171 | 지상 1층 | -510 | 바닥 : A1-14-03A-시멘트모르타르(고름용), 도막방수, 시멘트모르타르(보호용), 자기질타일 (90mm) | KBIMS-스테인리스 스틸_도금
3146276 | 202 | 지상 3층 | 0 | 레벨 : 지상 3층 | KBIMS-스테인리스 스틸_도금
3146278 | 203 | 지상 3층 | 0 | 레벨 : 지상 3층 | KBIMS-스테인리스 스틸_도금
3146335 | 222 | 지상 4층 | 0 | 레벨 : 지상 4층 | KBIMS-스테인리스 스틸_도금
3146337 | 221 | 지상 4층 | 0 | 레벨 : 지상 4층 | KBIMS-스테인리스 스틸_도금
3146394 | 225 | 지상 5층 | 0 | 레벨 : 지상 5층 | KBIMS-스테인리스 스틸_도금
3146396 | 226 | 지상 5층 | 0 | 레벨 : 지상 5층 | KBIMS-스테인리스 스틸_도금
3146453 | 240 | 지상 6층 | 0 | 레벨 : 지상 6층 | KBIMS-스테인리스 스틸_도금
3146455 | 241 | 지상 6층 | 0 | 레벨 : 지상 6층 | KBIMS-스테인리스 스틸_도금
3146512 | 266 | 지상 7층 | 0 | 레벨 : 지상 7층 | KBIMS-스테인리스 스틸_도금
3146514 | 267 | 지상 7층 | 0 | 레벨 : 지상 7층 | KBIMS-스테인리스 스틸_도금
3146571 | 278 | 지상 8층 | 0 | 레벨 : 지상 8층 | KBIMS-스테인리스 스틸_도금
3146573 | 279 | 지상 8층 | 0 | 레벨 : 지상 8층 | KBIMS-스테인리스 스틸_도금
3146630 | 297 | 지상 9층 | 0 | 레벨 : 지상 9층 | KBIMS-스테인리스 스틸_도금
3146632 | 298 | 지상 9층 | 0 | 레벨 : 지상 9층 | KBIMS-스테인리스 스틸_도금
3146689 | 312 | 지상 10층 | 0 | 레벨 : 지상 10층 | KBIMS-스테인리스 스틸_도금
3146691 | 313 | 지상 10층 | 0 | 레벨 : 지상 10층 | KBIMS-스테인리스 스틸_도금

# IfcFurnishingElement: PF591-대변기용 장애인 손잡이(상하가동식):PF591-대변기용 장애인 손잡이(상하가동식) (21)
Type - Material: KBIMS-스테인리스 스틸_도금 (4)
Type - ID 데이터 - OmniClass 번호: 23.75.00.00; OmniClass 제목: Climate Control (HVAC); 단가: 0; 유형 이름: PF591-대변기용 장애인 손잡이(상하가동식)
Type - 구속조건 - 기본 높이: 0 mm
Type - 기타 - 카테고리: 가구; KBIMS-부위코드: E713; 제작정보: AIBIM-2023; 조달청표준공사코드: APA18; 패밀리 이름: PF591-대변기용 장애인 손잡이(상하가동식)
Type - 치수 - 가로: 560 mm; 높이: 250 mm; 세로: 100 mm
Pset_QuantityTakeOff - Reference: PF591-대변기용 장애인 손잡이(상하가동식)
공정 - 생성 공정: 새 구성
구속조건 - 가까운 요소로 이동: no
기타 - 유형: PF591-대변기용 장애인 손잡이(상하가동식); 유형 ID: 6418508; 패밀리: PF591-대변기용 장애인 손잡이(상하가동식); 패밀리 및 유형: PF591-대변기용 장애인 손잡이(상하가동식): PF591-대변기용 장애인 손잡이(상하가동식)
치수 - 면적: 0.150103 m2; 체적: 0.00189882 m3
Name (PF591-대변기용 장애인 손잡이(상하가동식):PF591-대변기용 장애인 손잡이(상하가동식):...) | In | 레벨 | 호스트에서의 간격띄우기 (mm) | 레벨로부터의 높이 (mm) | 호스트 | Material
3146218 | 170 | 지상 1층 | 0 | -510 | 바닥 : A1-14-03A-시멘트모르타르(고름용), 도막방수, 시멘트모르타르(보호용), 자기질타일 (90mm)
3146220 | 171 | 지상 1층 | 0 | -510 | 바닥 : A1-14-03A-시멘트모르타르(고름용), 도막방수, 시멘트모르타르(보호용), 자기질타일 (90mm) | KBIMS-스테인리스 스틸_도금
7700322 | 지상 1층 | 지상 1층 | 0 | -600 | 바닥 : SL111-철근콘크리트구조 바닥 200mm_S4
7705761 | 188 | 지상 2층 | 0 | 40 | 바닥 : A1-14-03A-시멘트모르타르(고름용), 도막방수, 시멘트모르타르(보호용), 자기질타일 (90mm) | KBIMS-스테인리스 스틸_도금
7706118 | 202 | 지상 3층 | 0 | 40 | 바닥 : A1-14-03A-시멘트모르타르(고름용), 도막방수, 시멘트모르타르(보호용), 자기질타일 (90mm) | KBIMS-스테인리스 스틸_도금
7706175 | 222 | 지상 4층 | 0 | 40 | 바닥 : A1-14-03A-시멘트모르타르(고름용), 도막방수, 시멘트모르타르(보호용), 자기질타일 (90mm) | KBIMS-스테인리스 스틸_도금
7706232 | 225 | 지상 5층 | 0 | 40 | 바닥 : A1-14-03A-시멘트모르타르(고름용), 도막방수, 시멘트모르타르(보호용), 자기질타일 (90mm) | KBIMS-스테인리스 스틸_도금
7706289 | 240 | 지상 6층 | 0 | 40 | 바닥 : A1-14-03A-시멘트모르타르(고름용), 도막방수, 시멘트모르타르(보호용), 자기질타일 (90mm) | KBIMS-스테인리스 스틸_도금
7706346 | 266 | 지상 7층 | 0 | 40 | 바닥 : A1-14-03A-시멘트모르타르(고름용), 도막방수, 시멘트모르타르(보호용), 자기질타일 (90mm) | KBIMS-스테인리스 스틸_도금
7706403 | 278 | 지상 8층 | 0 | 40 | 바닥 : A1-14-03A-시멘트모르타르(고름용), 도막방수, 시멘트모르타르(보호용), 자기질타일 (90mm) | KBIMS-스테인리스 스틸_도금
7706460 | 297 | 지상 9층 | 0 | 40 | 바닥 : A1-14-03A-시멘트모르타르(고름용), 도막방수, 시멘트모르타르(보호용), 자기질타일 (90mm) | KBIMS-스테인리스 스틸_도금
7706517 | 312 | 지상 10층 | 0 | 0 | 레벨 : 지상 10층 | KBIMS-스테인리스 스틸_도금
7707622 | 189 | 지상 2층 | -40 | 0 | 바닥 : A1-14-03A-시멘트모르타르(고름용), 도막방수, 시멘트모르타르(보호용), 자기질타일 (90mm) | KBIMS-스테인리스 스틸_도금
7707854 | 203 | 지상 3층 | -40 | 0 | 바닥 : A1-14-03A-시멘트모르타르(고름용), 도막방수, 시멘트모르타르(보호용), 자기질타일 (90mm) | KBIMS-스테인리스 스틸_도금
7707895 | 221 | 지상 4층 | -40 | 0 | 바닥 : A1-14-03A-시멘트모르타르(고름용), 도막방수, 시멘트모르타르(보호용), 자기질타일 (90mm) | KBIMS-스테인리스 스틸_도금
7707936 | 226 | 지상 5층 | -40 | 0 | 바닥 : A1-14-03A-시멘트모르타르(고름용), 도막방수, 시멘트모르타르(보호용), 자기질타일 (90mm) | KBIMS-스테인리스 스틸_도금
7707977 | 241 | 지상 6층 | -40 | 0 | 바닥 : A1-14-03A-시멘트모르타르(고름용), 도막방수, 시멘트모르타르(보호용), 자기질타일 (90mm) | KBIMS-스테인리스 스틸_도금
7708018 | 267 | 지상 7층 | -40 | 0 | 바닥 : A1-14-03A-시멘트모르타르(고름용), 도막방수, 시멘트모르타르(보호용), 자기질타일 (90mm) | KBIMS-스테인리스 스틸_도금
7708059 | 279 | 지상 8층 | -40 | 0 | 바닥 : A1-14-03A-시멘트모르타르(고름용), 도막방수, 시멘트모르타르(보호용), 자기질타일 (90mm) | KBIMS-스테인리스 스틸_도금
7708100 | 298 | 지상 9층 | -40 | 0 | 바닥 : A1-14-03A-시멘트모르타르(고름용), 도막방수, 시멘트모르타르(보호용), 자기질타일 (90mm) | KBIMS-스테인리스 스틸_도금
7708141 | 313 | 지상 10층 | -40 | -40 | 레벨 : 지상 10층 | KBIMS-스테인리스 스틸_도금

# IfcFurnishingElement: SE251-장애인전용 표시:SE251-장애인전용 표시 (20)
Type - Material: KBIMS-노면용 페인트_진하늘색 (2)
Type - ID 데이터 - 유형 이름: SE251-장애인전용 표시
Type - 구속조건 - 기본 높이: 0 mm
Type - 기타 - 카테고리: 가구; KBIMS-부위코드: E77; 제작정보: AIBIM-2023; 조달청표준공사코드: CLH2603; 패밀리 이름: SE251-장애인전용 표시
Type - 치수 - 높이: 0 mm
Pset_QuantityTakeOff - Reference: SE251-장애인전용 표시
공정 - 생성 공정: 새 구성
구속조건 - 가까운 요소로 이동: no
기타 - 유형: SE251-장애인전용 표시; 유형 ID: 3121236; 패밀리: SE251-장애인전용 표시; 패밀리 및 유형: SE251-장애인전용 표시: SE251-장애인전용 표시
치수 - 면적: 0.117875 m2; 체적: 0.000182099 m3
Name (SE251-장애인전용 표시:SE251-장애인전용 표시:...) | In | 레벨 | 호스트에서의 간격띄우기 (mm) | 레벨로부터의 높이 (mm) | 호스트 | Material
3146200 | 170 | 지상 1층 | 0 | -510 | 바닥 : A1-14-03A-시멘트모르타르(고름용), 도막방수, 시멘트모르타르(보호용), 자기질타일 (90mm)
3146201 | 171 | 지상 1층 | 0 | -510 | 바닥 : A1-14-03A-시멘트모르타르(고름용), 도막방수, 시멘트모르타르(보호용), 자기질타일 (90mm) | KBIMS-노면용 페인트_진하늘색
7705760 | 188 | 지상 2층 | 90 | 40 | 바닥 : SL111-철근콘크리트구조 바닥 150mm_S4 | KBIMS-노면용 페인트_진하늘색
7706117 | 202 | 지상 3층 | 0 | 40 | 바닥 : A1-14-03A-시멘트모르타르(고름용), 도막방수, 시멘트모르타르(보호용), 자기질타일 (90mm) | KBIMS-노면용 페인트_진하늘색
7706174 | 222 | 지상 4층 | 0 | 40 | 바닥 : A1-14-03A-시멘트모르타르(고름용), 도막방수, 시멘트모르타르(보호용), 자기질타일 (90mm) | KBIMS-노면용 페인트_진하늘색
7706231 | 225 | 지상 5층 | 0 | 40 | 바닥 : A1-14-03A-시멘트모르타르(고름용), 도막방수, 시멘트모르타르(보호용), 자기질타일 (90mm) | KBIMS-노면용 페인트_진하늘색
7706288 | 240 | 지상 6층 | 0 | 40 | 바닥 : A1-14-03A-시멘트모르타르(고름용), 도막방수, 시멘트모르타르(보호용), 자기질타일 (90mm) | KBIMS-노면용 페인트_진하늘색
7706345 | 266 | 지상 7층 | 0 | 40 | 바닥 : A1-14-03A-시멘트모르타르(고름용), 도막방수, 시멘트모르타르(보호용), 자기질타일 (90mm) | KBIMS-노면용 페인트_진하늘색
7706402 | 278 | 지상 8층 | 0 | 40 | 바닥 : A1-14-03A-시멘트모르타르(고름용), 도막방수, 시멘트모르타르(보호용), 자기질타일 (90mm) | KBIMS-노면용 페인트_진하늘색
7706459 | 297 | 지상 9층 | 0 | 40 | 바닥 : A1-14-03A-시멘트모르타르(고름용), 도막방수, 시멘트모르타르(보호용), 자기질타일 (90mm) | KBIMS-노면용 페인트_진하늘색
7706516 | 지상 10층 | 지상 10층 | 0 | 0 | 레벨 : 지상 10층 | KBIMS-노면용 페인트_진하늘색
7707621 | 189 | 지상 2층 | 90 | 40 | 바닥 : SL111-철근콘크리트구조 바닥 150mm_S4 | KBIMS-노면용 페인트_진하늘색
7707853 | 203 | 지상 3층 | 0 | 40 | 바닥 : A1-14-03A-시멘트모르타르(고름용), 도막방수, 시멘트모르타르(보호용), 자기질타일 (90mm) | KBIMS-노면용 페인트_진하늘색
7707894 | 221 | 지상 4층 | 0 | 40 | 바닥 : A1-14-03A-시멘트모르타르(고름용), 도막방수, 시멘트모르타르(보호용), 자기질타일 (90mm) | KBIMS-노면용 페인트_진하늘색
7707935 | 226 | 지상 5층 | 0 | 40 | 바닥 : A1-14-03A-시멘트모르타르(고름용), 도막방수, 시멘트모르타르(보호용), 자기질타일 (90mm) | KBIMS-노면용 페인트_진하늘색
7707976 | 241 | 지상 6층 | 0 | 40 | 바닥 : A1-14-03A-시멘트모르타르(고름용), 도막방수, 시멘트모르타르(보호용), 자기질타일 (90mm) | KBIMS-노면용 페인트_진하늘색
7708017 | 267 | 지상 7층 | 0 | 40 | 바닥 : A1-14-03A-시멘트모르타르(고름용), 도막방수, 시멘트모르타르(보호용), 자기질타일 (90mm) | KBIMS-노면용 페인트_진하늘색
7708058 | 279 | 지상 8층 | 0 | 40 | 바닥 : A1-14-03A-시멘트모르타르(고름용), 도막방수, 시멘트모르타르(보호용), 자기질타일 (90mm) | KBIMS-노면용 페인트_진하늘색
7708099 | 298 | 지상 9층 | 0 | 40 | 바닥 : A1-14-03A-시멘트모르타르(고름용), 도막방수, 시멘트모르타르(보호용), 자기질타일 (90mm) | KBIMS-노면용 페인트_진하늘색
7708140 | 지상 10층 | 지상 10층 | 0 | 0 | 레벨 : 지상 10층 | KBIMS-노면용 페인트_진하늘색

# IfcGroup (5)
기타 - 카테고리: 면적 양식
Name | 이름
Rentable | Rentable
건축 면적 | 건축 면적
Gross Building | Gross Building
용도구획 | 용도구획
방화구획 | 방화구획

# IfcGroup: 모델 그룹:MEP 2, 모델 그룹:MEP 2:7855242
구속조건 - 원래 레벨 간격띄우기: 1180 mm; 참조 레벨: 지상 1층
기타 - 유형: MEP 2; 유형 ID: 7856198; 카테고리: 모델 그룹; 패밀리: 모델 그룹; 패밀리 및 유형: 모델 그룹: MEP 2
ID 데이터(Type) - 유형 이름: MEP 2
기타(Type) - 카테고리: 모델 그룹; 패밀리 이름: 모델 그룹

# IfcMember: 직사각형 멀리언:CW200-직사각형 멀리언 100 x 100mm (117)
Type - PredefinedType: MULLION; Material: <Unnamed>
Type - ID 데이터 - 유형 이름: CW200-직사각형 멀리언 100 x 100mm
Type - 구속조건 - 각도: 0 deg; 간격띄우기: 0 mm
Type - 기타 - 카테고리: 커튼월 멀리언; KBIMS-부위코드: E336; 조달청표준공사코드: ALC1; 패밀리 이름: 직사각형 멀리언
Type - 시공 - 위치: 면과 직각; 코너 멀리언: no; 프로파일: 시스템 멀리언 프로파일: 직사각형; 두께: 100 mm
Type - 치수 - 사이드 1의 폭: 50 mm; 사이드 2의 폭: 50 mm
Type - Pset_MemberCommon - IsExternal: no
공정 - 생성 공정: 새 구성
기타 - 패밀리: 직사각형 멀리언; 유형: CW200-직사각형 멀리언 100 x 100mm; 유형 ID: 3165390; 패밀리 및 유형: 직사각형 멀리언: CW200-직사각형 멀리언 100 x 100mm
Pset_MemberCommon - Reference: CW200-직사각형 멀리언 100 x 100mm
Pset_QuantityTakeOff - Reference: CW200-직사각형 멀리언 100 x 100mm
Name (직사각형 멀리언:CW200-직사각형 멀리언 100 x 100mm:...) | In | 레벨 | 호스트 ID | 길이 (mm) = Span (mm) | 면적 (m2) = CrossSectionArea (m2) | 체적 (m3) = NetVolume (m3) | NetSurfaceArea (m2)
2850817 | 지상 1층 | 지상 1층 | 2850019 | 2100 | 0.43 | 0.021 | 0.85
2851169 | 지상 1층 | 지상 1층 | 2850019 | 1920 | 0.394 | 0.0192 | 0.778
2864682 | 지상 1층 | 지상 1층 | 2864007 | 2100 | 0.43 | 0.021 | 0.85
2864747 | 지상 1층 | 지상 1층 | 2864007 | 1420 | 0.294 | 0.0142 | 0.578
2866272 | 지상 1층 | 지상 1층 | 2865038 | 1580 | 0.326 | 0.0158 | 0.642
2866273 | 지상 1층 | 지상 1층 | 2865038 | 1800 | 0.37 | 0.018 | 0.73
2875701 | 지상 1층 | 지상 1층 | 2875696 | 2100 | 0.43 | 0.021 | 0.85
2876777 | 지상 1층 | 지상 1층 | 2875696 | 1420 | 0.294 | 0.0142 | 0.578
2923467 | 지상 2층 | 지상 2층 | 2923462 | 2100 | 0.43 | 0.021 | 0.85
2924246 | 지상 2층 | 지상 2층 | 2923462 | 920 | 0.194 | 0.0092 | 0.378
2923554 | 지상 2층 | 지상 2층 | 2923549 | 2100 | 0.43 | 0.021 | 0.85
2923555 | 지상 2층 | 지상 2층 | 2923549 | 920 | 0.194 | 0.0092 | 0.378
2924470 | 지상 2층 | 지상 2층 | 2923549 | 920 | 0.194 | 0.0092 | 0.378
2924471 | 지상 2층 | 지상 2층 | 2923549 | 2100 | 0.43 | 0.021 | 0.85
2923621 | 지상 2층 | 지상 2층 | 2923615 | 920 | 0.194 | 0.0092 | 0.378
2924903 | 지상 2층 | 지상 2층 | 2923615 | 2100 | 0.43 | 0.021 | 0.85
2927269 | 지상 3층 | 지상 3층 | 2927264 | 950 | 0.2 | 0.0095 | 0.39
2927270 | 지상 3층 | 지상 3층 | 2927264 | 1070 | 0.224 | 0.0107 | 0.438
2929187 | 지상 3층 | 지상 3층 | 2927264 | 1070 | 0.224 | 0.0107 | 0.438
2929188 | 지상 3층 | 지상 3층 | 2927264 | 600 | 0.13 | 0.006 | 0.24
2929442 | 지상 3층 | 지상 3층 | 2927264 | 600 | 0.13 | 0.006 | 0.24
2929443 | 지상 3층 | 지상 3층 | 2927264 | 950 | 0.2 | 0.0095 | 0.39
2936728 | 지상 4층 | 지상 4층 | 2936724 | 1450 | 0.3 | 0.0145 | 0.59
2936732 | 지상 4층 | 지상 4층 | 2936724 | 1100 | 0.23 | 0.011 | 0.45
2936737 | 지상 4층 | 지상 4층 | 2936724 | 600 | 0.13 | 0.006 | 0.24
2937980 | 지상 4층 | 지상 4층 | 2936724 | 950 | 0.2 | 0.0095 | 0.38
2945779 | 지상 3층 | 지상 3층 | 2945775 | 950 | 0.2 | 0.0095 | 0.39
2945783 | 지상 3층 | 지상 3층 | 2945775 | 1070 | 0.224 | 0.0107 | 0.438
2945788 | 지상 3층 | 지상 3층 | 2945775 | 600 | 0.13 | 0.006 | 0.24
2948720 | 지상 4층 | 지상 4층 | 2948716 | 1450 | 0.3 | 0.0145 | 0.59
2948724 | 지상 4층 | 지상 4층 | 2948716 | 1050 | 0.22 | 0.0105 | 0.43
2948728 | 지상 4층 | 지상 4층 | 2948716 | 600 | 0.13 | 0.006 | 0.24
2949771 | 지상 4층 | 지상 4층 | 2948716 | 1000 | 0.21 | 0.01 | 0.4
2960450 | 지상 10층 | 지상 10층 | 2960446 | 300 | 0.07 | 0.003 | 0.13
2960454 | 지상 10층 | 지상 10층 | 2960446 | 600 | 0.13 | 0.006 | 0.24
2960459 | 지상 10층 | 지상 10층 | 2960446 | 2100 | 0.43 | 0.021 | 0.85
2970489 | 지상 10층 | 지상 10층 | 2970485 | 300 | 0.07 | 0.003 | 0.13
2970493 | 지상 10층 | 지상 10층 | 2970485 | 600 | 0.13 | 0.006 | 0.24
2970498 | 지상 10층 | 지상 10층 | 2970485 | 2100 | 0.43 | 0.021 | 0.85
5389074 | 지상 4층 | 지상 4층 | 5389070 | 2100 | 0.43 | 0.021 | 0.85
5389090 | 지상 4층 | 지상 4층 | 5389070 | 520 | 0.114 | 0.0052 | 0.218
5389525 | 지상 4층 | 지상 4층 | 5389520 | 520 | 0.114 | 0.0052 | 0.218
5389535 | 지상 4층 | 지상 4층 | 5389520 | 2100 | 0.43 | 0.021 | 0.85
5393181 | 지상 9층 | 지상 9층 | 5393177 | 2100 | 0.43 | 0.021 | 0.85
5393197 | 지상 9층 | 지상 9층 | 5393177 | 920 | 0.194 | 0.0092 | 0.378
5393188 | 지상 9층 | 지상 9층 | 5393183 | 920 | 0.194 | 0.0092 | 0.378
5393209 | 지상 9층 | 지상 9층 | 5393183 | 2100 | 0.43 | 0.021 | 0.85
5393194 | 지상 9층 | 지상 9층 | 5393189 | 920 | 0.194 | 0.0092 | 0.378
5393224 | 지상 9층 | 지상 9층 | 5393189 | 2100 | 0.43 | 0.021 | 0.85
5403432 | 지상 5층 | 지상 5층 | 5403428 | 2100 | 0.43 | 0.021 | 0.85
5403436 | 지상 5층 | 지상 5층 | 5403428 | 520 | 0.114 | 0.0052 | 0.218
5403444 | 지상 5층 | 지상 5층 | 5403439 | 520 | 0.114 | 0.0052 | 0.218
5403454 | 지상 5층 | 지상 5층 | 5403439 | 2100 | 0.43 | 0.021 | 0.85
5403470 | 지상 6층 | 지상 6층 | 5403466 | 2100 | 0.43 | 0.021 | 0.85
5403474 | 지상 6층 | 지상 6층 | 5403466 | 520 | 0.114 | 0.0052 | 0.218
5403482 | 지상 6층 | 지상 6층 | 5403477 | 520 | 0.114 | 0.0052 | 0.218
5403492 | 지상 6층 | 지상 6층 | 5403477 | 2100 | 0.43 | 0.021 | 0.85
5403508 | 지상 7층 | 지상 7층 | 5403504 | 2100 | 0.43 | 0.021 | 0.85
5403512 | 지상 7층 | 지상 7층 | 5403504 | 520 | 0.114 | 0.0052 | 0.218
5403520 | 지상 7층 | 지상 7층 | 5403515 | 520 | 0.114 | 0.0052 | 0.218
5403530 | 지상 7층 | 지상 7층 | 5403515 | 2100 | 0.43 | 0.021 | 0.85
5403546 | 지상 8층 | 지상 8층 | 5403542 | 2100 | 0.43 | 0.021 | 0.85
5403550 | 지상 8층 | 지상 8층 | 5403542 | 520 | 0.114 | 0.0052 | 0.218
5403558 | 지상 8층 | 지상 8층 | 5403553 | 520 | 0.114 | 0.0052 | 0.218
5403568 | 지상 8층 | 지상 8층 | 5403553 | 2100 | 0.43 | 0.021 | 0.85
5403585 | 지상 4층 | 지상 4층 | 5403580 | 520 | 0.114 | 0.0052 | 0.218
5403589 | 지상 4층 | 지상 4층 | 5403580 | 2100 | 0.43 | 0.021 | 0.85
5403606 | 지상 5층 | 지상 5층 | 5403601 | 520 | 0.114 | 0.0052 | 0.218
5403610 | 지상 5층 | 지상 5층 | 5403601 | 2100 | 0.43 | 0.021 | 0.85
5403625 | 지상 6층 | 지상 6층 | 5403620 | 520 | 0.114 | 0.0052 | 0.218
5403629 | 지상 6층 | 지상 6층 | 5403620 | 2100 | 0.43 | 0.021 | 0.85
5403644 | 지상 7층 | 지상 7층 | 5403639 | 520 | 0.114 | 0.0052 | 0.218
5403648 | 지상 7층 | 지상 7층 | 5403639 | 2100 | 0.43 | 0.021 | 0.85
5403663 | 지상 8층 | 지상 8층 | 5403658 | 520 | 0.114 | 0.0052 | 0.218
5403667 | 지상 8층 | 지상 8층 | 5403658 | 2100 | 0.43 | 0.021 | 0.85
5403681 | 지상 10층 | 지상 10층 | 5403677 | 2100 | 0.43 | 0.021 | 0.85
5403685 | 지상 10층 | 지상 10층 | 5403677 | 1420 | 0.294 | 0.0142 | 0.578
5403695 | 지상 10층 | 지상 10층 | 5403690 | 1420 | 0.294 | 0.0142 | 0.578
5403705 | 지상 10층 | 지상 10층 | 5403690 | 2100 | 0.43 | 0.021 | 0.85
5403731 | 지상 10층 | 지상 10층 | 5403726 | 1420 | 0.294 | 0.0142 | 0.578
5403735 | 지상 10층 | 지상 10층 | 5403726 | 2100 | 0.43 | 0.021 | 0.85
5405790 | 지상 3층 | 지상 3층 | 5405786 | 2100 | 0.43 | 0.021 | 0.85
5405794 | 지상 3층 | 지상 3층 | 5405786 | 520 | 0.114 | 0.0052 | 0.218
5405802 | 지상 3층 | 지상 3층 | 5405797 | 520 | 0.114 | 0.0052 | 0.218
5405812 | 지상 3층 | 지상 3층 | 5405797 | 2100 | 0.43 | 0.021 | 0.85
5818112 | 지상 9층 | 지상 9층 | 5818108 | 300 | 0.07 | 0.003 | 0.13
5818115 | 지상 9층 | 지상 9층 | 5818108 | 600 | 0.13 | 0.006 | 0.24
5818119 | 지상 9층 | 지상 9층 | 5818108 | 1600 | 0.33 | 0.016 | 0.65
5818685 | 지상 9층 | 지상 9층 | 5818681 | 300 | 0.07 | 0.003 | 0.13
5818689 | 지상 9층 | 지상 9층 | 5818681 | 600 | 0.13 | 0.006 | 0.24
5818694 | 지상 9층 | 지상 9층 | 5818681 | 1600 | 0.33 | 0.016 | 0.65
5819258 | 지상 8층 | 지상 8층 | 5819254 | 300 | 0.07 | 0.003 | 0.13
5819261 | 지상 8층 | 지상 8층 | 5819254 | 600 | 0.13 | 0.006 | 0.24
5819265 | 지상 8층 | 지상 8층 | 5819254 | 1100 | 0.23 | 0.011 | 0.45
5819646 | 지상 8층 | 지상 8층 | 5819642 | 300 | 0.07 | 0.003 | 0.13
5819650 | 지상 8층 | 지상 8층 | 5819642 | 600 | 0.13 | 0.006 | 0.24
5819655 | 지상 8층 | 지상 8층 | 5819642 | 1100 | 0.23 | 0.011 | 0.45
5820125 | 지상 7층 | 지상 7층 | 5820121 | 300 | 0.07 | 0.003 | 0.13
5820128 | 지상 7층 | 지상 7층 | 5820121 | 600 | 0.13 | 0.006 | 0.24
5820132 | 지상 7층 | 지상 7층 | 5820121 | 1100 | 0.23 | 0.011 | 0.45
5820513 | 지상 7층 | 지상 7층 | 5820509 | 300 | 0.07 | 0.003 | 0.13
5820517 | 지상 7층 | 지상 7층 | 5820509 | 600 | 0.13 | 0.006 | 0.24
5820522 | 지상 7층 | 지상 7층 | 5820509 | 1100 | 0.23 | 0.011 | 0.45
5821013 | 지상 6층 | 지상 6층 | 5821009 | 300 | 0.07 | 0.003 | 0.13
5821016 | 지상 6층 | 지상 6층 | 5821009 | 600 | 0.13 | 0.006 | 0.24
5821020 | 지상 6층 | 지상 6층 | 5821009 | 1100 | 0.23 | 0.011 | 0.45
5821401 | 지상 6층 | 지상 6층 | 5821397 | 300 | 0.07 | 0.003 | 0.13
5821405 | 지상 6층 | 지상 6층 | 5821397 | 600 | 0.13 | 0.006 | 0.24
5821410 | 지상 6층 | 지상 6층 | 5821397 | 1100 | 0.23 | 0.011 | 0.45
5821882 | 지상 5층 | 지상 5층 | 5821878 | 300 | 0.07 | 0.003 | 0.13
5821885 | 지상 5층 | 지상 5층 | 5821878 | 600 | 0.13 | 0.006 | 0.24
5821889 | 지상 5층 | 지상 5층 | 5821878 | 1100 | 0.23 | 0.011 | 0.45
5822270 | 지상 5층 | 지상 5층 | 5822266 | 300 | 0.07 | 0.003 | 0.13
5822274 | 지상 5층 | 지상 5층 | 5822266 | 600 | 0.13 | 0.006 | 0.24
5822279 | 지상 5층 | 지상 5층 | 5822266 | 1100 | 0.23 | 0.011 | 0.45
7697254 | 지상 3층 | 지상 3층 | 7697250 | 520 | 0.114 | 0.0052 | 0.218
7697258 | 지상 3층 | 지상 3층 | 7697250 | 2100 | 0.43 | 0.021 | 0.85

# IfcMember: 직사각형 멀리언:CW200-직사각형 멀리언 50x200mm (8700)
Type - PredefinedType: MULLION; Material: <Unnamed>
Type - ID 데이터 - 유형 이름: CW200-직사각형 멀리언 50x200mm
Type - 구속조건 - 각도: 0 deg; 간격띄우기: 0 mm
Type - 기타 - 카테고리: 커튼월 멀리언; KBIMS-부위코드: E336; 조달청표준공사코드: ALC1; 패밀리 이름: 직사각형 멀리언
Type - 시공 - 두께: 200 mm; 위치: 면과 직각; 코너 멀리언: no; 프로파일: 시스템 멀리언 프로파일: 직사각형
Type - 치수 - 사이드 1의 폭: 25 mm; 사이드 2의 폭: 25 mm
Type - Pset_MemberCommon - IsExternal: no
공정 - 생성 공정: 새 구성
기타 - 유형: CW200-직사각형 멀리언 50x200mm; 유형 ID: 6832447; 패밀리: 직사각형 멀리언; 패밀리 및 유형: 직사각형 멀리언: CW200-직사각형 멀리언 50x200mm
Pset_MemberCommon - Reference: CW200-직사각형 멀리언 50x200mm
Pset_QuantityTakeOff - Reference: CW200-직사각형 멀리언 50x200mm
Name (직사각형 멀리언:CW200-직사각형 멀리언 50x200mm:...) | In | 레벨 | 호스트 ID | 길이 (mm) = Span (mm) | 면적 (m2) = CrossSectionArea (m2) | 체적 (m3) = NetVolume (m3) | NetSurfaceArea (m2)
2836339 | 지상 1층 | 지상 1층 | 2836336 | 925 | 0.24125 | 0.00925 | 0.4825
2836340 | 지상 1층 | 지상 1층 | 2836336 | 1175 | 0.30375 | 0.01175 | 0.6075
2836341 | 지상 1층 | 지상 1층 | 2836336 | 2100 | 0.535 | 0.021 | 1.06
2836342 | 지상 1층 | 지상 1층 | 2836336 | 1420 | 0.365 | 0.0142 | 0.72
2836876 | 지상 1층 | 지상 1층 | 2836336 | 1175 | 0.30375 | 0.01175 | 0.6075
2836877 | 지상 1층 | 지상 1층 | 2836336 | 1100 | 0.285 | 0.011 | 0.57
2836878 | 지상 1층 | 지상 1층 | 2836336 | 2100 | 0.535 | 0.021 | 1.06
2836964 | 지상 1층 | 지상 1층 | 2836336 | 1100 | 0.285 | 0.011 | 0.57
2836966 | 지상 1층 | 지상 1층 | 2836336 | 2100 | 0.535 | 0.021 | 1.06
2837037 | 지상 1층 | 지상 1층 | 2836336 | 950 | 0.2475 | 0.0095 | 0.495
2837038 | 지상 1층 | 지상 1층 | 2836336 | 1250 | 0.3225 | 0.0125 | 0.645
2837039 | 지상 1층 | 지상 1층 | 2836336 | 2100 | 0.535 | 0.021 | 1.06
2837130 | 지상 1층 | 지상 1층 | 2836336 | 1420 | 0.365 | 0.0142 | 0.72
2837131 | 지상 1층 | 지상 1층 | 2836336 | 2100 | 0.535 | 0.021 | 1.06
2837132 | 지상 1층 | 지상 1층 | 2836336 | 1175 | 0.30375 | 0.01175 | 0.6075
2837133 | 지상 1층 | 지상 1층 | 2836336 | 1100 | 0.285 | 0.011 | 0.57
2837134 | 지상 1층 | 지상 1층 | 2836336 | 950 | 0.2475 | 0.0095 | 0.495
2837135 | 지상 1층 | 지상 1층 | 2836336 | 1250 | 0.3225 | 0.0125 | 0.645
2837136 | 지상 1층 | 지상 1층 | 2836336 | 1420 | 0.365 | 0.0142 | 0.72
2837137 | 지상 1층 | 지상 1층 | 2836336 | 1420 | 0.365 | 0.0142 | 0.72
2837138 | 지상 1층 | 지상 1층 | 2836336 | 1420 | 0.365 | 0.0142 | 0.72
2837263 | 지상 1층 | 지상 1층 | 2836336 | 1250 | 0.3225 | 0.0125 | 0.645
2837264 | 지상 1층 | 지상 1층 | 2836336 | 1450 | 0.3725 | 0.0145 | 0.745
2837265 | 지상 1층 | 지상 1층 | 2836336 | 1450 | 0.3725 | 0.0145 | 0.745
2837266 | 지상 1층 | 지상 1층 | 2836336 | 2100 | 0.535 | 0.021 | 1.06
2837267 | 지상 1층 | 지상 1층 | 2836336 | 1420 | 0.365 | 0.0142 | 0.72
2837375 | 지상 1층 | 지상 1층 | 2836336 | 1450 | 0.3725 | 0.0145 | 0.745
2837377 | 지상 1층 | 지상 1층 | 2836336 | 925 | 0.24125 | 0.00925 | 0.4825
2837378 | 지상 1층 | 지상 1층 | 2836336 | 2100 | 0.535 | 0.021 | 1.06
2837379 | 지상 1층 | 지상 1층 | 2836336 | 1420 | 0.365 | 0.0142 | 0.72
2838633 | 지상 1층 | 지상 1층 | 2838631 | 1075 | 0.27875 | 0.01075 | 0.5575
2838634 | 지상 1층 | 지상 1층 | 2838631 | 1175 | 0.30375 | 0.01175 | 0.6075
2838635 | 지상 1층 | 지상 1층 | 2838631 | 2100 | 0.535 | 0.021 | 1.06
2838636 | 지상 1층 | 지상 1층 | 2838631 | 1420 | 0.365 | 0.0142 | 0.72
2838639 | 지상 1층 | 지상 1층 | 2838631 | 1175 | 0.30375 | 0.01175 | 0.6075
2838640 | 지상 1층 | 지상 1층 | 2838631 | 1100 | 0.285 | 0.011 | 0.57
2838641 | 지상 1층 | 지상 1층 | 2838631 | 2100 | 0.535 | 0.021 | 1.06
2838644 | 지상 1층 | 지상 1층 | 2838631 | 1100 | 0.285 | 0.011 | 0.57
2838646 | 지상 1층 | 지상 1층 | 2838631 | 2100 | 0.535 | 0.021 | 1.06
2838649 | 지상 1층 | 지상 1층 | 2838631 | 950 | 0.2475 | 0.0095 | 0.495
2838650 | 지상 1층 | 지상 1층 | 2838631 | 975 | 0.25375 | 0.00975 | 0.5075
2838651 | 지상 1층 | 지상 1층 | 2838631 | 2100 | 0.535 | 0.021 | 1.06
2838657 | 지상 1층 | 지상 1층 | 2838631 | 1420 | 0.365 | 0.0142 | 0.72
2838658 | 지상 1층 | 지상 1층 | 2838631 | 2100 | 0.535 | 0.021 | 1.06
2838659 | 지상 1층 | 지상 1층 | 2838631 | 1175 | 0.30375 | 0.01175 | 0.6075
2838660 | 지상 1층 | 지상 1층 | 2838631 | 1100 | 0.285 | 0.011 | 0.57
2838661 | 지상 1층 | 지상 1층 | 2838631 | 950 | 0.2475 | 0.0095 | 0.495
2838662 | 지상 1층 | 지상 1층 | 2838631 | 975 | 0.25375 | 0.00975 | 0.5075
2838663 | 지상 1층 | 지상 1층 | 2838631 | 1420 | 0.365 | 0.0142 | 0.72
2838664 | 지상 1층 | 지상 1층 | 2838631 | 1420 | 0.365 | 0.0142 | 0.72
2838665 | 지상 1층 | 지상 1층 | 2838631 | 1420 | 0.365 | 0.0142 | 0.72
2838669 | 지상 1층 | 지상 1층 | 2838631 | 975 | 0.25375 | 0.00975 | 0.5075
2838670 | 지상 1층 | 지상 1층 | 2838631 | 975 | 0.25375 | 0.00975 | 0.5075
2838671 | 지상 1층 | 지상 1층 | 2838631 | 975 | 0.25375 | 0.00975 | 0.5075
2838672 | 지상 1층 | 지상 1층 | 2838631 | 2100 | 0.535 | 0.021 | 1.06
2838673 | 지상 1층 | 지상 1층 | 2838631 | 1420 | 0.365 | 0.0142 | 0.72
2838677 | 지상 1층 | 지상 1층 | 2838631 | 975 | 0.25375 | 0.00975 | 0.5075
2838679 | 지상 1층 | 지상 1층 | 2838631 | 1075 | 0.27875 | 0.01075 | 0.5575
2838680 | 지상 1층 | 지상 1층 | 2838631 | 2100 | 0.535 | 0.021 | 1.06
2838681 | 지상 1층 | 지상 1층 | 2838631 | 1420 | 0.365 | 0.0142 | 0.72
2839310 | 지상 1층 | 지상 1층 | 2839308 | 2275 | 0.57875 | 0.02275 | 1.1575
2839312 | 지상 1층 | 지상 1층 | 2839308 | 2100 | 0.535 | 0.021 | 1.06
2839313 | 지상 1층 | 지상 1층 | 2839308 | 1420 | 0.365 | 0.0142 | 0.72
2839316 | 지상 1층 | 지상 1층 | 2839308 | 1120 | 0.29 | 0.0112 | 0.58
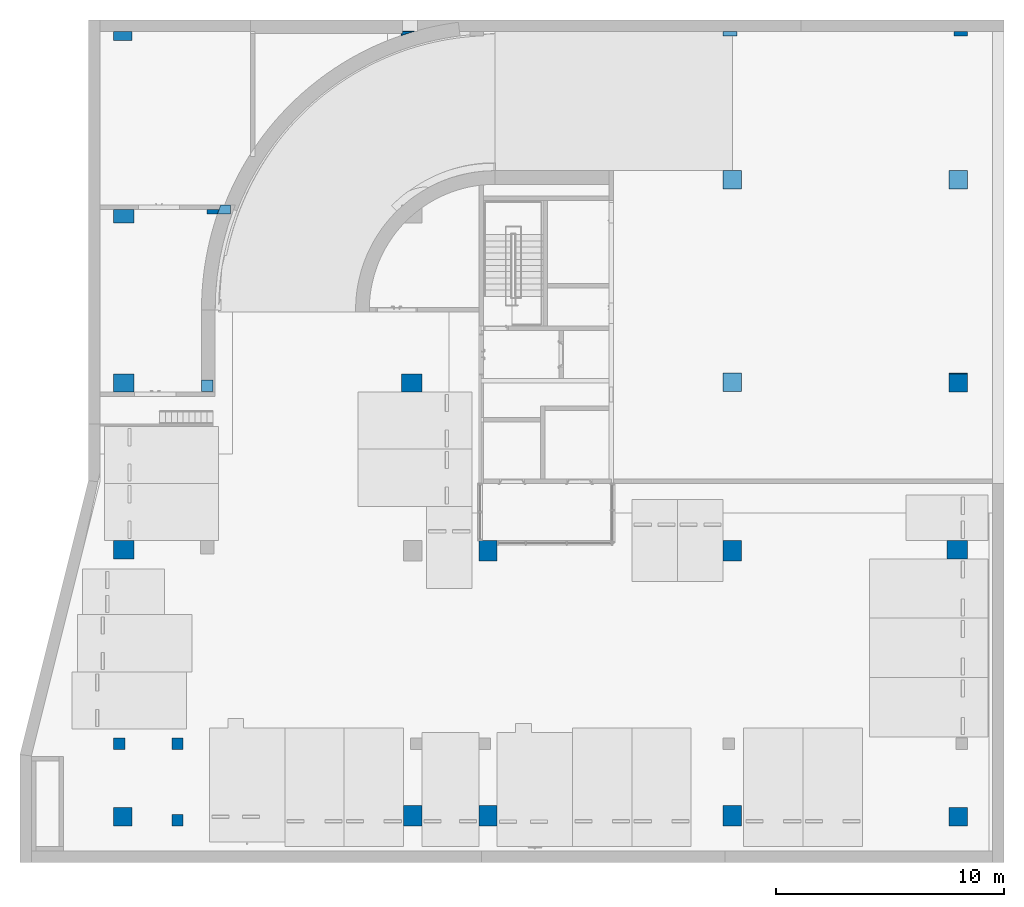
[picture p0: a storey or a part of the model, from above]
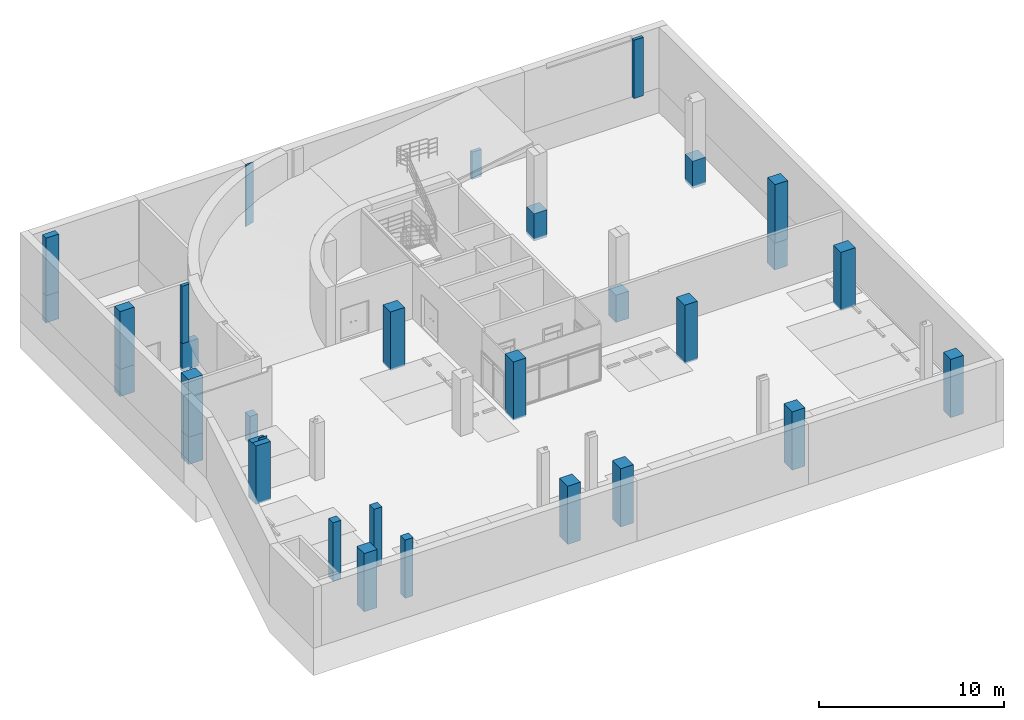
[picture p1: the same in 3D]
Properties of the parts of a building model (IFC2X3), part 14 of 39

# IfcMember: 직사각형 멀리언:CW200-직사각형 멀리언 50x200mm (8700)
Name (직사각형 멀리언:CW200-직사각형 멀리언 50x200mm:...) | In | 레벨 | 호스트 ID | 길이 (mm) = Span (mm) | 면적 (m2) = CrossSectionArea (m2) | 체적 (m3) = NetVolume (m3) | NetSurfaceArea (m2)
2839318 | 지상 1층 | 지상 1층 | 2839308 | 2100 | 0.535 | 0.021 | 1.06
2839321 | 지상 1층 | 지상 1층 | 2839308 | 960 | 0.25 | 0.0096 | 0.5
2839322 | 지상 1층 | 지상 1층 | 2839308 | 1500 | 0.385 | 0.015 | 0.77
2839323 | 지상 1층 | 지상 1층 | 2839308 | 2100 | 0.535 | 0.021 | 1.06
2839326 | 지상 1층 | 지상 1층 | 2839308 | 1500 | 0.385 | 0.015 | 0.77
2839327 | 지상 1층 | 지상 1층 | 2839308 | 1500 | 0.385 | 0.015 | 0.77
2839328 | 지상 1층 | 지상 1층 | 2839308 | 2100 | 0.535 | 0.021 | 1.06
2839334 | 지상 1층 | 지상 1층 | 2839308 | 1420 | 0.365 | 0.0142 | 0.72
2839335 | 지상 1층 | 지상 1층 | 2839308 | 2100 | 0.535 | 0.021 | 1.06
2839336 | 지상 1층 | 지상 1층 | 2839308 | 1025.02 | 0.266254 | 0.0102502 | 0.532509
2839337 | 지상 1층 | 지상 1층 | 2839308 | 960 | 0.25 | 0.0096 | 0.5
2839338 | 지상 1층 | 지상 1층 | 2839308 | 1500 | 0.385 | 0.015 | 0.77
2839339 | 지상 1층 | 지상 1층 | 2839308 | 1500 | 0.385 | 0.015 | 0.77
2839340 | 지상 1층 | 지상 1층 | 2839308 | 1420 | 0.365 | 0.0142 | 0.72
2839341 | 지상 1층 | 지상 1층 | 2839308 | 1420 | 0.365 | 0.0142 | 0.72
2839342 | 지상 1층 | 지상 1층 | 2839308 | 1420 | 0.365 | 0.0142 | 0.72
2839346 | 지상 1층 | 지상 1층 | 2839308 | 1500 | 0.385 | 0.015 | 0.77
2839348 | 지상 1층 | 지상 1층 | 2839308 | 950 | 0.2475 | 0.0095 | 0.495
2839349 | 지상 1층 | 지상 1층 | 2839308 | 2100 | 0.535 | 0.021 | 1.06
2839350 | 지상 1층 | 지상 1층 | 2839308 | 1420 | 0.365 | 0.0142 | 0.72
2839354 | 지상 1층 | 지상 1층 | 2839308 | 950 | 0.2475 | 0.0095 | 0.495
2839355 | 지상 1층 | 지상 1층 | 2839308 | 2275 | 0.57875 | 0.02275 | 1.1575
2839356 | 지상 1층 | 지상 1층 | 2839308 | 2275 | 0.57875 | 0.02275 | 1.1575
2839357 | 지상 1층 | 지상 1층 | 2839308 | 2100 | 0.535 | 0.021 | 1.06
2839358 | 지상 1층 | 지상 1층 | 2839308 | 1420 | 0.365 | 0.0142 | 0.72
2839610 | 지상 1층 | 지상 1층 | 2839308 | 1025.02 | 0.266254 | 0.0102502 | 0.532509
2839611 | 지상 1층 | 지상 1층 | 2839308 | 1120 | 0.29 | 0.0112 | 0.58
2839612 | 지상 1층 | 지상 1층 | 2839308 | 1120 | 0.29 | 0.0112 | 0.58
2839613 | 지상 1층 | 지상 1층 | 2839308 | 2100 | 0.535 | 0.021 | 1.06
2839614 | 지상 1층 | 지상 1층 | 2839308 | 1420 | 0.365 | 0.0142 | 0.72
2839812 | 지상 1층 | 지상 1층 | 2839308 | 1120 | 0.29 | 0.0112 | 0.58
2839813 | 지상 1층 | 지상 1층 | 2839308 | 1120 | 0.29 | 0.0112 | 0.58
2839814 | 지상 1층 | 지상 1층 | 2839308 | 1120 | 0.29 | 0.0112 | 0.58
2839815 | 지상 1층 | 지상 1층 | 2839308 | 2100 | 0.535 | 0.021 | 1.06
2839816 | 지상 1층 | 지상 1층 | 2839308 | 1420 | 0.365 | 0.0142 | 0.72
2842074 | 지상 1층 | 지상 1층 | 2842071 | 1769.21 | 0.452302 | 0.0176921 | 0.904604
2842075 | 지상 1층 | 지상 1층 | 2842071 | 1730.79 | 0.442698 | 0.0173079 | 0.885396
2842076 | 지상 1층 | 지상 1층 | 2842071 | 2000 | 0.51 | 0.02 | 1.01
2842077 | 지상 1층 | 지상 1층 | 2842071 | 1520 | 0.39 | 0.0152 | 0.77
2842505 | 지상 1층 | 지상 1층 | 2842071 | 1600 | 0.41 | 0.016 | 0.82
2842506 | 지상 1층 | 지상 1층 | 2842071 | 1600 | 0.41 | 0.016 | 0.82
2842507 | 지상 1층 | 지상 1층 | 2842071 | 2000 | 0.51 | 0.02 | 1.01
2842691 | 지상 1층 | 지상 1층 | 2842071 | 1520 | 0.39 | 0.0152 | 0.77
2842692 | 지상 1층 | 지상 1층 | 2842071 | 2000 | 0.51 | 0.02 | 1.01
2842693 | 지상 1층 | 지상 1층 | 2842071 | 1730.79 | 0.442698 | 0.0173079 | 0.885396
2842694 | 지상 1층 | 지상 1층 | 2842071 | 1600 | 0.41 | 0.016 | 0.82
2842695 | 지상 1층 | 지상 1층 | 2842071 | 1520 | 0.39 | 0.0152 | 0.77
2842788 | 지상 1층 | 지상 1층 | 2842071 | 1730.79 | 0.442698 | 0.0173079 | 0.885396
2842789 | 지상 1층 | 지상 1층 | 2842071 | 1600 | 0.41 | 0.016 | 0.82
2842790 | 지상 1층 | 지상 1층 | 2842071 | 1600 | 0.41 | 0.016 | 0.82
2842791 | 지상 1층 | 지상 1층 | 2842071 | 2000 | 0.51 | 0.02 | 1.01
2842792 | 지상 1층 | 지상 1층 | 2842071 | 1520 | 0.39 | 0.0152 | 0.77
2842908 | 지상 1층 | 지상 1층 | 2842071 | 1600 | 0.41 | 0.016 | 0.82
2842909 | 지상 1층 | 지상 1층 | 2842071 | 1600 | 0.41 | 0.016 | 0.82
2842910 | 지상 1층 | 지상 1층 | 2842071 | 1600 | 0.41 | 0.016 | 0.82
2842911 | 지상 1층 | 지상 1층 | 2842071 | 2000 | 0.51 | 0.02 | 1.01
2842912 | 지상 1층 | 지상 1층 | 2842071 | 1520 | 0.39 | 0.0152 | 0.77
2843049 | 지상 1층 | 지상 1층 | 2842071 | 1600 | 0.41 | 0.016 | 0.82
2843050 | 지상 1층 | 지상 1층 | 2842071 | 1600 | 0.41 | 0.016 | 0.82
2843051 | 지상 1층 | 지상 1층 | 2842071 | 1600 | 0.41 | 0.016 | 0.82
2843052 | 지상 1층 | 지상 1층 | 2842071 | 2000 | 0.51 | 0.02 | 1.01
2843053 | 지상 1층 | 지상 1층 | 2842071 | 1520 | 0.39 | 0.0152 | 0.77
2843123 | 지상 1층 | 지상 1층 | 2842071 | 1600 | 0.41 | 0.016 | 0.82
2843124 | 지상 1층 | 지상 1층 | 2842071 | 1600 | 0.41 | 0.016 | 0.82
2843125 | 지상 1층 | 지상 1층 | 2842071 | 1600 | 0.41 | 0.016 | 0.82
2843126 | 지상 1층 | 지상 1층 | 2842071 | 2000 | 0.51 | 0.02 | 1.01
2843127 | 지상 1층 | 지상 1층 | 2842071 | 1520 | 0.39 | 0.0152 | 0.77
2843240 | 지상 1층 | 지상 1층 | 2842071 | 1600 | 0.41 | 0.016 | 0.82
2843241 | 지상 1층 | 지상 1층 | 2842071 | 1769.21 | 0.452302 | 0.0176921 | 0.904604
2843242 | 지상 1층 | 지상 1층 | 2842071 | 1769.21 | 0.452302 | 0.0176921 | 0.904604
2843243 | 지상 1층 | 지상 1층 | 2842071 | 2000 | 0.51 | 0.02 | 1.01
2843244 | 지상 1층 | 지상 1층 | 2842071 | 1520 | 0.39 | 0.0152 | 0.77
2844133 | 지상 1층 | 지상 1층 | 2844131 | 1375 | 0.35375 | 0.01375 | 0.7075
2844135 | 지상 1층 | 지상 1층 | 2844131 | 2100 | 0.535 | 0.021 | 1.06
2844136 | 지상 1층 | 지상 1층 | 2844131 | 1420 | 0.365 | 0.0142 | 0.72
2844139 | 지상 1층 | 지상 1층 | 2844131 | 1200 | 0.31 | 0.012 | 0.62
2844140 | 지상 1층 | 지상 1층 | 2844131 | 1200 | 0.31 | 0.012 | 0.62
2844141 | 지상 1층 | 지상 1층 | 2844131 | 2100 | 0.535 | 0.021 | 1.06
2844145 | 지상 1층 | 지상 1층 | 2844131 | 1420 | 0.365 | 0.0142 | 0.72
2844146 | 지상 1층 | 지상 1층 | 2844131 | 2100 | 0.535 | 0.021 | 1.06
2844147 | 지상 1층 | 지상 1층 | 2844131 | 1025.02 | 0.266254 | 0.0102502 | 0.532509
2844148 | 지상 1층 | 지상 1층 | 2844131 | 1200 | 0.31 | 0.012 | 0.62
2844149 | 지상 1층 | 지상 1층 | 2844131 | 1420 | 0.365 | 0.0142 | 0.72
2844153 | 지상 1층 | 지상 1층 | 2844131 | 1025.02 | 0.266254 | 0.0102502 | 0.532509
2844154 | 지상 1층 | 지상 1층 | 2844131 | 1200 | 0.31 | 0.012 | 0.62
2844155 | 지상 1층 | 지상 1층 | 2844131 | 1200 | 0.31 | 0.012 | 0.62
2844156 | 지상 1층 | 지상 1층 | 2844131 | 2100 | 0.535 | 0.021 | 1.06
2844157 | 지상 1층 | 지상 1층 | 2844131 | 1420 | 0.365 | 0.0142 | 0.72
2844161 | 지상 1층 | 지상 1층 | 2844131 | 1200 | 0.31 | 0.012 | 0.62
2844162 | 지상 1층 | 지상 1층 | 2844131 | 1200 | 0.31 | 0.012 | 0.62
2844163 | 지상 1층 | 지상 1층 | 2844131 | 1200 | 0.31 | 0.012 | 0.62
2844164 | 지상 1층 | 지상 1층 | 2844131 | 2100 | 0.535 | 0.021 | 1.06
2844165 | 지상 1층 | 지상 1층 | 2844131 | 1420 | 0.365 | 0.0142 | 0.72
2844169 | 지상 1층 | 지상 1층 | 2844131 | 1200 | 0.31 | 0.012 | 0.62
2844171 | 지상 1층 | 지상 1층 | 2844131 | 990 | 0.2575 | 0.0099 | 0.515
2844172 | 지상 1층 | 지상 1층 | 2844131 | 2100 | 0.535 | 0.021 | 1.06
2844173 | 지상 1층 | 지상 1층 | 2844131 | 1420 | 0.365 | 0.0142 | 0.72
2844177 | 지상 1층 | 지상 1층 | 2844131 | 990 | 0.2575 | 0.0099 | 0.515
2844178 | 지상 1층 | 지상 1층 | 2844131 | 1230 | 0.3175 | 0.0123 | 0.635
2844179 | 지상 1층 | 지상 1층 | 2844131 | 1230 | 0.3175 | 0.0123 | 0.635
2844180 | 지상 1층 | 지상 1층 | 2844131 | 2100 | 0.535 | 0.021 | 1.06
2844181 | 지상 1층 | 지상 1층 | 2844131 | 1420 | 0.365 | 0.0142 | 0.72
2844501 | 지상 1층 | 지상 1층 | 2844131 | 1230 | 0.3175 | 0.0123 | 0.635
2844502 | 지상 1층 | 지상 1층 | 2844131 | 1230 | 0.3175 | 0.0123 | 0.635
2844503 | 지상 1층 | 지상 1층 | 2844131 | 1230 | 0.3175 | 0.0123 | 0.635
2844504 | 지상 1층 | 지상 1층 | 2844131 | 2100 | 0.535 | 0.021 | 1.06
2844505 | 지상 1층 | 지상 1층 | 2844131 | 1420 | 0.365 | 0.0142 | 0.72
2844563 | 지상 1층 | 지상 1층 | 2844131 | 1230 | 0.3175 | 0.0123 | 0.635
2844564 | 지상 1층 | 지상 1층 | 2844131 | 1375 | 0.35375 | 0.01375 | 0.7075
2844565 | 지상 1층 | 지상 1층 | 2844131 | 1375 | 0.35375 | 0.01375 | 0.7075
2844566 | 지상 1층 | 지상 1층 | 2844131 | 2100 | 0.535 | 0.021 | 1.06
2844567 | 지상 1층 | 지상 1층 | 2844131 | 1420 | 0.365 | 0.0142 | 0.72
2844811 | 지상 1층 | 지상 1층 | 2844807 | 1524.65 | 0.391162 | 0.0152465 | 0.782323
2844812 | 지상 1층 | 지상 1층 | 2844807 | 1507.35 | 0.386838 | 0.0150735 | 0.773677
2844813 | 지상 1층 | 지상 1층 | 2844807 | 2000 | 0.51 | 0.02 | 1.01
2844814 | 지상 1층 | 지상 1층 | 2844807 | 1520 | 0.39 | 0.0152 | 0.77
2845159 | 지상 1층 | 지상 1층 | 2844807 | 1520 | 0.39 | 0.0152 | 0.77
2845160 | 지상 1층 | 지상 1층 | 2844807 | 2000 | 0.51 | 0.02 | 1.01
2845161 | 지상 1층 | 지상 1층 | 2844807 | 1507.35 | 0.386838 | 0.0150735 | 0.773677
2845561 | 지상 1층 | 지상 1층 | 2844807 | 1507.35 | 0.386838 | 0.0150735 | 0.773677
2845562 | 지상 1층 | 지상 1층 | 2844807 | 1400 | 0.36 | 0.014 | 0.72
2845563 | 지상 1층 | 지상 1층 | 2844807 | 1400 | 0.36 | 0.014 | 0.72
2845565 | 지상 1층 | 지상 1층 | 2844807 | 2000 | 0.51 | 0.02 | 1.01
2845566 | 지상 1층 | 지상 1층 | 2844807 | 1520 | 0.39 | 0.0152 | 0.77
2845622 | 지상 1층 | 지상 1층 | 2844807 | 1400 | 0.36 | 0.014 | 0.72
2845623 | 지상 1층 | 지상 1층 | 2844807 | 1400 | 0.36 | 0.014 | 0.72
2845624 | 지상 1층 | 지상 1층 | 2844807 | 1400 | 0.36 | 0.014 | 0.72
2845626 | 지상 1층 | 지상 1층 | 2844807 | 2000 | 0.51 | 0.02 | 1.01
2845627 | 지상 1층 | 지상 1층 | 2844807 | 1520 | 0.39 | 0.0152 | 0.77
2845723 | 지상 1층 | 지상 1층 | 2844807 | 1400 | 0.36 | 0.014 | 0.72
2845724 | 지상 1층 | 지상 1층 | 2844807 | 1400 | 0.36 | 0.014 | 0.72
2845725 | 지상 1층 | 지상 1층 | 2844807 | 1400 | 0.36 | 0.014 | 0.72
2845727 | 지상 1층 | 지상 1층 | 2844807 | 2000 | 0.51 | 0.02 | 1.01
2845728 | 지상 1층 | 지상 1층 | 2844807 | 1520 | 0.39 | 0.0152 | 0.77
2845817 | 지상 1층 | 지상 1층 | 2844807 | 1400 | 0.36 | 0.014 | 0.72
2845818 | 지상 1층 | 지상 1층 | 2844807 | 1500 | 0.385 | 0.015 | 0.77
2845819 | 지상 1층 | 지상 1층 | 2844807 | 1500 | 0.385 | 0.015 | 0.77
2845821 | 지상 1층 | 지상 1층 | 2844807 | 2000 | 0.51 | 0.02 | 1.01
2845822 | 지상 1층 | 지상 1층 | 2844807 | 1520 | 0.39 | 0.0152 | 0.77
2845931 | 지상 1층 | 지상 1층 | 2844807 | 1500 | 0.385 | 0.015 | 0.77
2845932 | 지상 1층 | 지상 1층 | 2844807 | 1524.65 | 0.391162 | 0.0152465 | 0.782323
2845933 | 지상 1층 | 지상 1층 | 2844807 | 1524.65 | 0.391162 | 0.0152465 | 0.782323
2845935 | 지상 1층 | 지상 1층 | 2844807 | 2000 | 0.51 | 0.02 | 1.01
2845936 | 지상 1층 | 지상 1층 | 2844807 | 1520 | 0.39 | 0.0152 | 0.77
2847230 | 지상 1층 | 지상 1층 | 2847227 | 975 | 0.25375 | 0.00975 | 0.5075
2847231 | 지상 1층 | 지상 1층 | 2847227 | 1204.98 | 0.311246 | 0.0120498 | 0.622492
2847232 | 지상 1층 | 지상 1층 | 2847227 | 2100 | 0.535 | 0.021 | 1.06
2847233 | 지상 1층 | 지상 1층 | 2847227 | 1420 | 0.365 | 0.0142 | 0.72
2848237 | 지상 1층 | 지상 1층 | 2847227 | 1204.98 | 0.311246 | 0.0120498 | 0.622492
2848238 | 지상 1층 | 지상 1층 | 2847227 | 1080 | 0.28 | 0.0108 | 0.56
2848239 | 지상 1층 | 지상 1층 | 2847227 | 2100 | 0.535 | 0.021 | 1.06
2848311 | 지상 1층 | 지상 1층 | 2847227 | 1080 | 0.28 | 0.0108 | 0.56
2848313 | 지상 1층 | 지상 1층 | 2847227 | 2100 | 0.535 | 0.021 | 1.06
2848384 | 지상 1층 | 지상 1층 | 2847227 | 950 | 0.2475 | 0.0095 | 0.495
2848385 | 지상 1층 | 지상 1층 | 2847227 | 1500 | 0.385 | 0.015 | 0.77
2848386 | 지상 1층 | 지상 1층 | 2847227 | 2100 | 0.535 | 0.021 | 1.06
2848455 | 지상 1층 | 지상 1층 | 2847227 | 1500 | 0.385 | 0.015 | 0.77
2848456 | 지상 1층 | 지상 1층 | 2847227 | 1500 | 0.385 | 0.015 | 0.77
2848457 | 지상 1층 | 지상 1층 | 2847227 | 2100 | 0.535 | 0.021 | 1.06
2848536 | 지상 1층 | 지상 1층 | 2847227 | 1500 | 0.385 | 0.015 | 0.77
2848538 | 지상 1층 | 지상 1층 | 2847227 | 2100 | 0.535 | 0.021 | 1.06
2848615 | 지상 1층 | 지상 1층 | 2847227 | 950 | 0.2475 | 0.0095 | 0.495
2848616 | 지상 1층 | 지상 1층 | 2847227 | 1120 | 0.29 | 0.0112 | 0.58
2848617 | 지상 1층 | 지상 1층 | 2847227 | 2100 | 0.535 | 0.021 | 1.06
2848791 | 지상 1층 | 지상 1층 | 2847227 | 1120 | 0.29 | 0.0112 | 0.58
2848792 | 지상 1층 | 지상 1층 | 2847227 | 1120 | 0.29 | 0.0112 | 0.58
2848793 | 지상 1층 | 지상 1층 | 2847227 | 2100 | 0.535 | 0.021 | 1.06
2848876 | 지상 1층 | 지상 1층 | 2847227 | 1120 | 0.29 | 0.0112 | 0.58
2848878 | 지상 1층 | 지상 1층 | 2847227 | 2100 | 0.535 | 0.021 | 1.06
2849193 | 지상 1층 | 지상 1층 | 2847227 | 1420 | 0.365 | 0.0142 | 0.72
2849194 | 지상 1층 | 지상 1층 | 2847227 | 2100 | 0.535 | 0.021 | 1.06
2849195 | 지상 1층 | 지상 1층 | 2847227 | 1204.98 | 0.311246 | 0.0120498 | 0.622492
2849196 | 지상 1층 | 지상 1층 | 2847227 | 1080 | 0.28 | 0.0108 | 0.56
2849197 | 지상 1층 | 지상 1층 | 2847227 | 950 | 0.2475 | 0.0095 | 0.495
2849198 | 지상 1층 | 지상 1층 | 2847227 | 1500 | 0.385 | 0.015 | 0.77
2849199 | 지상 1층 | 지상 1층 | 2847227 | 1500 | 0.385 | 0.015 | 0.77
2849200 | 지상 1층 | 지상 1층 | 2847227 | 950 | 0.2475 | 0.0095 | 0.495
2849201 | 지상 1층 | 지상 1층 | 2847227 | 1120 | 0.29 | 0.0112 | 0.58
2849203 | 지상 1층 | 지상 1층 | 2847227 | 1120 | 0.29 | 0.0112 | 0.58
2849204 | 지상 1층 | 지상 1층 | 2847227 | 975 | 0.25375 | 0.00975 | 0.5075
2849205 | 지상 1층 | 지상 1층 | 2847227 | 1420 | 0.365 | 0.0142 | 0.72
2849206 | 지상 1층 | 지상 1층 | 2847227 | 1420 | 0.365 | 0.0142 | 0.72
2849207 | 지상 1층 | 지상 1층 | 2847227 | 1420 | 0.365 | 0.0142 | 0.72
2849208 | 지상 1층 | 지상 1층 | 2847227 | 1420 | 0.365 | 0.0142 | 0.72
2849209 | 지상 1층 | 지상 1층 | 2847227 | 1420 | 0.365 | 0.0142 | 0.72
2849210 | 지상 1층 | 지상 1층 | 2847227 | 1420 | 0.365 | 0.0142 | 0.72
2849212 | 지상 1층 | 지상 1층 | 2847227 | 1420 | 0.365 | 0.0142 | 0.72
2849213 | 지상 1층 | 지상 1층 | 2847227 | 1420 | 0.365 | 0.0142 | 0.72
2850022 | 지상 1층 | 지상 1층 | 2850019 | 1445.03 | 0.371259 | 0.0144503 | 0.742517
2850023 | 지상 1층 | 지상 1층 | 2850019 | 300 | 0.085 | 0.003 | 0.17
2850024 | 지상 1층 | 지상 1층 | 2850019 | 2100 | 0.535 | 0.021 | 1.06
2850025 | 지상 1층 | 지상 1층 | 2850019 | 1920 | 0.49 | 0.0192 | 0.97
2850465 | 지상 1층 | 지상 1층 | 2850019 | 325 | 0.09125 | 0.00325 | 0.1725
2850467 | 지상 1층 | 지상 1층 | 2850019 | 2125 | 0.54125 | 0.02125 | 1.0825
2850607 | 지상 1층 | 지상 1층 | 2850019 | 870 | 0.2275 | 0.0087 | 0.445
2850736 | 지상 1층 | 지상 1층 | 2850019 | 870 | 0.2275 | 0.0087 | 0.445
2850737 | 지상 1층 | 지상 1층 | 2850019 | 300 | 0.085 | 0.003 | 0.17
2850738 | 지상 1층 | 지상 1층 | 2850019 | 2125 | 0.54125 | 0.02125 | 1.0825
2850815 | 지상 1층 | 지상 1층 | 2850019 | 324.965 | 0.0912413 | 0.00324965 | 0.172483
2850889 | 지상 1층 | 지상 1층 | 2850019 | 1075 | 0.27875 | 0.01075 | 0.5575
2850890 | 지상 1층 | 지상 1층 | 2850019 | 1270 | 0.3275 | 0.0127 | 0.655
2850891 | 지상 1층 | 지상 1층 | 2850019 | 2100 | 0.535 | 0.021 | 1.06
2851158 | 지상 1층 | 지상 1층 | 2850019 | 1920 | 0.49 | 0.0192 | 0.97
2851159 | 지상 1층 | 지상 1층 | 2850019 | 2100 | 0.535 | 0.021 | 1.06
2851160 | 지상 1층 | 지상 1층 | 2850019 | 300 | 0.085 | 0.003 | 0.17
2851161 | 지상 1층 | 지상 1층 | 2850019 | 845 | 0.22125 | 0.00845 | 0.4425
2851162 | 지상 1층 | 지상 1층 | 2850019 | 845 | 0.22125 | 0.00845 | 0.4425
2851163 | 지상 1층 | 지상 1층 | 2850019 | 300 | 0.085 | 0.003 | 0.17
2851164 | 지상 1층 | 지상 1층 | 2850019 | 1075 | 0.27875 | 0.01075 | 0.5575
2851165 | 지상 1층 | 지상 1층 | 2850019 | 1270 | 0.3275 | 0.0127 | 0.655
2851170 | 지상 1층 | 지상 1층 | 2850019 | 1920 | 0.49 | 0.0192 | 0.97
2851647 | 지상 1층 | 지상 1층 | 2850019 | 1270 | 0.3275 | 0.0127 | 0.655
2851648 | 지상 1층 | 지상 1층 | 2850019 | 1445.03 | 0.371259 | 0.0144503 | 0.742517
2851649 | 지상 1층 | 지상 1층 | 2850019 | 1445.03 | 0.371259 | 0.0144503 | 0.742517
2851651 | 지상 1층 | 지상 1층 | 2850019 | 2100 | 0.535 | 0.021 | 1.06
2851652 | 지상 1층 | 지상 1층 | 2850019 | 1920 | 0.49 | 0.0192 | 0.97
2851884 | 지상 1층 | 지상 1층 | 2851881 | 1387.03 | 0.356759 | 0.0138703 | 0.713517
2851886 | 지상 1층 | 지상 1층 | 2851881 | 2100 | 0.535 | 0.021 | 1.06
2851887 | 지상 1층 | 지상 1층 | 2851881 | 1460 | 0.375 | 0.0146 | 0.74
2852138 | 지상 1층 | 지상 1층 | 2851881 | 1435 | 0.36875 | 0.01435 | 0.7275
2852139 | 지상 1층 | 지상 1층 | 2851881 | 2100 | 0.535 | 0.021 | 1.06
2852140 | 지상 1층 | 지상 1층 | 2851881 | 975 | 0.25375 | 0.00975 | 0.5075
2852265 | 지상 1층 | 지상 1층 | 2851881 | 1435 | 0.36875 | 0.01435 | 0.7375
2852266 | 지상 1층 | 지상 1층 | 2851881 | 1460 | 0.375 | 0.0146 | 0.73
2852267 | 지상 1층 | 지상 1층 | 2851881 | 975 | 0.25375 | 0.00975 | 0.5075
2852332 | 지상 1층 | 지상 1층 | 2851881 | 975 | 0.25375 | 0.00975 | 0.5075
2852333 | 지상 1층 | 지상 1층 | 2851881 | 1495 | 0.38375 | 0.01495 | 0.7675
2852334 | 지상 1층 | 지상 1층 | 2851881 | 1495 | 0.38375 | 0.01495 | 0.7675
2852335 | 지상 1층 | 지상 1층 | 2851881 | 1495 | 0.38375 | 0.01495 | 0.7675
2852336 | 지상 1층 | 지상 1층 | 2851881 | 2100 | 0.535 | 0.021 | 1.06
2852337 | 지상 1층 | 지상 1층 | 2851881 | 1460 | 0.375 | 0.0146 | 0.73
2852338 | 지상 1층 | 지상 1층 | 2851881 | 1460 | 0.375 | 0.0146 | 0.74
2852463 | 지상 1층 | 지상 1층 | 2851881 | 1495 | 0.38375 | 0.01495 | 0.7675
2852464 | 지상 1층 | 지상 1층 | 2851881 | 1495 | 0.38375 | 0.01495 | 0.7675
2852465 | 지상 1층 | 지상 1층 | 2851881 | 1495 | 0.38375 | 0.01495 | 0.7675
2852466 | 지상 1층 | 지상 1층 | 2851881 | 1495 | 0.38375 | 0.01495 | 0.7675
2852467 | 지상 1층 | 지상 1층 | 2851881 | 2100 | 0.535 | 0.021 | 1.06
2852468 | 지상 1층 | 지상 1층 | 2851881 | 1460 | 0.375 | 0.0146 | 0.73
2852469 | 지상 1층 | 지상 1층 | 2851881 | 1460 | 0.375 | 0.0146 | 0.74
2852578 | 지상 1층 | 지상 1층 | 2851881 | 1495 | 0.38375 | 0.01495 | 0.7675
2852580 | 지상 1층 | 지상 1층 | 2851881 | 950 | 0.2475 | 0.0095 | 0.495
2852581 | 지상 1층 | 지상 1층 | 2851881 | 950 | 0.2475 | 0.0095 | 0.495
2852582 | 지상 1층 | 지상 1층 | 2851881 | 2100 | 0.535 | 0.021 | 1.06
2852583 | 지상 1층 | 지상 1층 | 2851881 | 1460 | 0.375 | 0.0146 | 0.73
2852584 | 지상 1층 | 지상 1층 | 2851881 | 1460 | 0.375 | 0.0146 | 0.74
2852932 | 지상 1층 | 지상 1층 | 2851881 | 950 | 0.2475 | 0.0095 | 0.495
2852933 | 지상 1층 | 지상 1층 | 2851881 | 1330 | 0.3425 | 0.0133 | 0.685
2852934 | 지상 1층 | 지상 1층 | 2851881 | 1330 | 0.3425 | 0.0133 | 0.685
2852935 | 지상 1층 | 지상 1층 | 2851881 | 1330 | 0.3425 | 0.0133 | 0.685
2852936 | 지상 1층 | 지상 1층 | 2851881 | 2100 | 0.535 | 0.021 | 1.06
2852937 | 지상 1층 | 지상 1층 | 2851881 | 1460 | 0.375 | 0.0146 | 0.73
2852938 | 지상 1층 | 지상 1층 | 2851881 | 1460 | 0.375 | 0.0146 | 0.74
2853073 | 지상 1층 | 지상 1층 | 2851881 | 1330 | 0.3425 | 0.0133 | 0.685
2853074 | 지상 1층 | 지상 1층 | 2851881 | 1387.03 | 0.356759 | 0.0138703 | 0.713517
2853075 | 지상 1층 | 지상 1층 | 2851881 | 1387.03 | 0.356759 | 0.0138703 | 0.713517
2853076 | 지상 1층 | 지상 1층 | 2851881 | 1437.03 | 0.369259 | 0.0143703 | 0.738517
2853077 | 지상 1층 | 지상 1층 | 2851881 | 2100 | 0.535 | 0.021 | 1.06
2853078 | 지상 1층 | 지상 1층 | 2851881 | 1460 | 0.375 | 0.0146 | 0.73
2853079 | 지상 1층 | 지상 1층 | 2851881 | 1460 | 0.375 | 0.0146 | 0.74
2853673 | 지상 1층 | 지상 1층 | 2853669 | 175 | 0.05375 | 0.00175 | 0.1075
2853675 | 지상 1층 | 지상 1층 | 2853669 | 1050 | 0.2725 | 0.0105 | 0.535
2853676 | 지상 1층 | 지상 1층 | 2853669 | 970 | 0.2525 | 0.0097 | 0.495
2854187 | 지상 1층 | 지상 1층 | 2853669 | 1075 | 0.27875 | 0.01075 | 0.5575
2854188 | 지상 1층 | 지상 1층 | 2853669 | 175 | 0.05375 | 0.00175 | 0.1075
2854189 | 지상 1층 | 지상 1층 | 2853669 | 1050 | 0.2725 | 0.0105 | 0.535
2854329 | 지상 1층 | 지상 1층 | 2853669 | 970 | 0.2525 | 0.0097 | 0.495
2854330 | 지상 1층 | 지상 1층 | 2853669 | 1050 | 0.2725 | 0.0105 | 0.535
2854332 | 지상 1층 | 지상 1층 | 2853669 | 175 | 0.05375 | 0.00175 | 0.1075
2854333 | 지상 1층 | 지상 1층 | 2853669 | 970 | 0.2525 | 0.0097 | 0.495
2855067 | 지상 1층 | 지상 1층 | 2855064 | 1100 | 0.285 | 0.011 | 0.57
2855068 | 지상 1층 | 지상 1층 | 2855064 | 1100 | 0.285 | 0.011 | 0.57
2855069 | 지상 1층 | 지상 1층 | 2855064 | 2100 | 0.535 | 0.021 | 1.06
2855070 | 지상 1층 | 지상 1층 | 2855064 | 1420 | 0.365 | 0.0142 | 0.72
2855464 | 지상 1층 | 지상 1층 | 2855064 | 1420 | 0.365 | 0.0142 | 0.72
2855465 | 지상 1층 | 지상 1층 | 2855064 | 2100 | 0.535 | 0.021 | 1.06
2855466 | 지상 1층 | 지상 1층 | 2855064 | 1100 | 0.285 | 0.011 | 0.57
2855929 | 지상 1층 | 지상 1층 | 2855926 | 655.056 | 0.173764 | 0.00655056 | 0.337528
2855930 | 지상 1층 | 지상 1층 | 2855926 | 4262.41 | 1.0756 | 0.0426241 | 2.1512
2856633 | 지상 1층 | 지상 1층 | 2855926 | 1550 | 0.3975 | 0.0155 | 0.775
2856634 | 지상 1층 | 지상 1층 | 2855926 | 630.056 | 0.167514 | 0.00630056 | 0.335028
2856635 | 지상 1층 | 지상 1층 | 2855926 | 2125 | 0.54125 | 0.02125 | 1.0825
2856937 | 지상 1층 | 지상 1층 | 2855926 | 4287.41 | 1.08185 | 0.0428741 | 2.1537
2856939 | 지상 1층 | 지상 1층 | 2855926 | 2125 | 0.54125 | 0.02125 | 1.0825
2857081 | 지상 1층 | 지상 1층 | 2855926 | 4262.41 | 1.0756 | 0.0426241 | 2.1512
2857082 | 지상 1층 | 지상 1층 | 2855926 | 1500 | 0.385 | 0.015 | 0.77
2857083 | 지상 1층 | 지상 1층 | 2855926 | 630.056 | 0.167514 | 0.00630056 | 0.335028
2857420 | 지상 1층 | 지상 1층 | 2857417 | 275 | 0.07875 | 0.00275 | 0.1575
2857421 | 지상 1층 | 지상 1층 | 2857417 | 2100 | 0.535 | 0.021 | 1.06
2857422 | 지상 1층 | 지상 1층 | 2857417 | 1920 | 0.49 | 0.0192 | 0.97
2857425 | 지상 1층 | 지상 1층 | 2857417 | 1800 | 0.46 | 0.018 | 0.9
2857427 | 지상 1층 | 지상 1층 | 2857417 | 2125 | 0.54125 | 0.02125 | 1.0825
2857430 | 지상 1층 | 지상 1층 | 2857417 | 300 | 0.085 | 0.003 | 0.16
2857432 | 지상 1층 | 지상 1층 | 2857417 | 2125 | 0.54125 | 0.02125 | 1.0825
2857437 | 지상 1층 | 지상 1층 | 2857417 | 1920 | 0.49 | 0.0192 | 0.97
2857438 | 지상 1층 | 지상 1층 | 2857417 | 2100 | 0.535 | 0.021 | 1.06
2857439 | 지상 1층 | 지상 1층 | 2857417 | 275 | 0.07875 | 0.00275 | 0.1575
2857440 | 지상 1층 | 지상 1층 | 2857417 | 1750 | 0.4475 | 0.0175 | 0.895
5461778 | 지상 1층 | 지상 1층 | 2857417 | 300 | 0.085 | 0.003 | 0.16
5461779 | 지상 1층 | 지상 1층 | 2857417 | 275 | 0.07875 | 0.00275 | 0.1575
5461780 | 지상 1층 | 지상 1층 | 2857417 | 275 | 0.07875 | 0.00275 | 0.1575
2857504 | 지상 1층 | 지상 1층 | 2857502 | 300.118 | 0.0850294 | 0.00300118 | 0.160059
2857505 | 지상 1층 | 지상 1층 | 2857502 | 275 | 0.07875 | 0.00275 | 0.1575
2857506 | 지상 1층 | 지상 1층 | 2857502 | 2100 | 0.535 | 0.021 | 1.06
2857507 | 지상 1층 | 지상 1층 | 2857502 | 1420 | 0.365 | 0.0142 | 0.72
2857510 | 지상 1층 | 지상 1층 | 2857502 | 1800 | 0.46 | 0.018 | 0.9
2857511 | 지상 1층 | 지상 1층 | 2857502 | 275 | 0.07875 | 0.00275 | 0.1575
2857512 | 지상 1층 | 지상 1층 | 2857502 | 2125 | 0.54125 | 0.02125 | 1.0825
2857515 | 지상 1층 | 지상 1층 | 2857502 | 300 | 0.085 | 0.003 | 0.16
2857517 | 지상 1층 | 지상 1층 | 2857502 | 2125 | 0.54125 | 0.02125 | 1.0825
2857522 | 지상 1층 | 지상 1층 | 2857502 | 1420 | 0.365 | 0.0142 | 0.72
2857523 | 지상 1층 | 지상 1층 | 2857502 | 2100 | 0.535 | 0.021 | 1.06
2857524 | 지상 1층 | 지상 1층 | 2857502 | 275 | 0.07875 | 0.00275 | 0.1575
2857525 | 지상 1층 | 지상 1층 | 2857502 | 1750 | 0.4475 | 0.0175 | 0.895
2857526 | 지상 1층 | 지상 1층 | 2857502 | 275 | 0.07875 | 0.00275 | 0.1575
2864010 | 지상 1층 | 지상 1층 | 2864007 | 2925 | 0.74125 | 0.02925 | 1.4825
2864012 | 지상 1층 | 지상 1층 | 2864007 | 2100 | 0.535 | 0.021 | 1.06
2864013 | 지상 1층 | 지상 1층 | 2864007 | 1420 | 0.365 | 0.0142 | 0.72
2864519 | 지상 1층 | 지상 1층 | 2864007 | 2950 | 0.7475 | 0.0295 | 1.495
2864521 | 지상 1층 | 지상 1층 | 2864007 | 2100 | 0.535 | 0.021 | 1.06
2864599 | 지상 1층 | 지상 1층 | 2864007 | 1425 | 0.36625 | 0.01425 | 0.7325
2864601 | 지상 1층 | 지상 1층 | 2864007 | 2100 | 0.535 | 0.021 | 1.06
2864680 | 지상 1층 | 지상 1층 | 2864007 | 1400 | 0.36 | 0.014 | 0.72
2864741 | 지상 1층 | 지상 1층 | 2864007 | 1420 | 0.365 | 0.0142 | 0.72
2864742 | 지상 1층 | 지상 1층 | 2864007 | 2100 | 0.535 | 0.021 | 1.06
2864743 | 지상 1층 | 지상 1층 | 2864007 | 1400 | 0.36 | 0.014 | 0.72
2864744 | 지상 1층 | 지상 1층 | 2864007 | 1425 | 0.36625 | 0.01425 | 0.7325
2864745 | 지상 1층 | 지상 1층 | 2864007 | 2950 | 0.7475 | 0.0295 | 1.495
2864746 | 지상 1층 | 지상 1층 | 2864007 | 2925 | 0.74125 | 0.02925 | 1.4825
2864748 | 지상 1층 | 지상 1층 | 2864007 | 1420 | 0.365 | 0.0142 | 0.72
2864749 | 지상 1층 | 지상 1층 | 2864007 | 1420 | 0.365 | 0.0142 | 0.72
5476552 | 지상 1층 | 지상 1층 | 2864007 | 1400 | 0.36 | 0.014 | 0.72
5476553 | 지상 1층 | 지상 1층 | 2864007 | 2925 | 0.74125 | 0.02925 | 1.4825
5476554 | 지상 1층 | 지상 1층 | 2864007 | 2950 | 0.7475 | 0.0295 | 1.495
5476555 | 지상 1층 | 지상 1층 | 2864007 | 1425 | 0.36625 | 0.01425 | 0.7325
2865041 | 지상 1층 | 지상 1층 | 2865038 | 625 | 0.16625 | 0.00625 | 0.3325
2865043 | 지상 1층 | 지상 1층 | 2865038 | 1580 | 0.405 | 0.0158 | 0.8
2865929 | 지상 1층 | 지상 1층 | 2865038 | 1800 | 0.46 | 0.018 | 0.91
2865931 | 지상 1층 | 지상 1층 | 2865038 | 2237.49 | 0.569373 | 0.0223749 | 1.13875
2865977 | 지상 1층 | 지상 1층 | 2865038 | 2950 | 0.7475 | 0.0295 | 1.495
2865979 | 지상 1층 | 지상 1층 | 2865038 | 625 | 0.16625 | 0.00625 | 0.3325
2865980 | 지상 1층 | 지상 1층 | 2865038 | 1580 | 0.405 | 0.0158 | 0.8
2865981 | 지상 1층 | 지상 1층 | 2865038 | 1800 | 0.46 | 0.018 | 0.91
2866136 | 지상 1층 | 지상 1층 | 2865038 | 1425 | 0.36625 | 0.01425 | 0.7325
2866138 | 지상 1층 | 지상 1층 | 2865038 | 2950 | 0.7475 | 0.0295 | 1.495
2866139 | 지상 1층 | 지상 1층 | 2865038 | 1580 | 0.405 | 0.0158 | 0.8
2866140 | 지상 1층 | 지상 1층 | 2865038 | 1800 | 0.46 | 0.018 | 0.91
2866269 | 지상 1층 | 지상 1층 | 2865038 | 2237.49 | 0.569373 | 0.0223749 | 1.13875
2866271 | 지상 1층 | 지상 1층 | 2865038 | 1425 | 0.36625 | 0.01425 | 0.7325
5476594 | 지상 1층 | 지상 1층 | 2865038 | 2237.49 | 0.569373 | 0.0223749 | 1.13875
5476595 | 지상 1층 | 지상 1층 | 2865038 | 625 | 0.16625 | 0.00625 | 0.3325
5476596 | 지상 1층 | 지상 1층 | 2865038 | 2950 | 0.7475 | 0.0295 | 1.495
5476597 | 지상 1층 | 지상 1층 | 2865038 | 1425 | 0.36625 | 0.01425 | 0.7325
2867556 | 지상 1층 | 지상 1층 | 2867553 | 2275 | 0.57875 | 0.02275 | 1.1575
2867557 | 지상 1층 | 지상 1층 | 2867553 | 1125 | 0.29125 | 0.01125 | 0.5825
2867558 | 지상 1층 | 지상 1층 | 2867553 | 2100 | 0.535 | 0.021 | 1.06
2867559 | 지상 1층 | 지상 1층 | 2867553 | 1420 | 0.365 | 0.0142 | 0.72
2868083 | 지상 1층 | 지상 1층 | 2867553 | 2350 | 0.5975 | 0.0235 | 1.195
2868084 | 지상 1층 | 지상 1층 | 2867553 | 2700 | 0.685 | 0.027 | 1.37
2868085 | 지상 1층 | 지상 1층 | 2867553 | 2100 | 0.535 | 0.021 | 1.06
2868516 | 지상 1층 | 지상 1층 | 2867553 | 950 | 0.2475 | 0.0095 | 0.495
2868517 | 지상 1층 | 지상 1층 | 2867553 | 2275 | 0.57875 | 0.02275 | 1.1575
2868518 | 지상 1층 | 지상 1층 | 2867553 | 2100 | 0.535 | 0.021 | 1.06
2868618 | 지상 1층 | 지상 1층 | 2867553 | 950 | 0.2475 | 0.0095 | 0.495
2868720 | 지상 1층 | 지상 1층 | 2867553 | 2700 | 0.685 | 0.027 | 1.37
2868722 | 지상 1층 | 지상 1층 | 2867553 | 2100 | 0.535 | 0.021 | 1.06
2868815 | 지상 1층 | 지상 1층 | 2867553 | 1125 | 0.29125 | 0.01125 | 0.5825
2868816 | 지상 1층 | 지상 1층 | 2867553 | 2350 | 0.5975 | 0.0235 | 1.195
2868817 | 지상 1층 | 지상 1층 | 2867553 | 2100 | 0.535 | 0.021 | 1.06
2868953 | 지상 1층 | 지상 1층 | 2867553 | 1420 | 0.365 | 0.0142 | 0.72
2868954 | 지상 1층 | 지상 1층 | 2867553 | 2100 | 0.535 | 0.021 | 1.06
2868955 | 지상 1층 | 지상 1층 | 2867553 | 1125 | 0.29125 | 0.01125 | 0.5825
2868956 | 지상 1층 | 지상 1층 | 2867553 | 2350 | 0.5975 | 0.0235 | 1.195
2868957 | 지상 1층 | 지상 1층 | 2867553 | 2700 | 0.685 | 0.027 | 1.37
2868958 | 지상 1층 | 지상 1층 | 2867553 | 950 | 0.2475 | 0.0095 | 0.495
2868959 | 지상 1층 | 지상 1층 | 2867553 | 950 | 0.2475 | 0.0095 | 0.495
2868960 | 지상 1층 | 지상 1층 | 2867553 | 2275 | 0.57875 | 0.02275 | 1.1575
2868961 | 지상 1층 | 지상 1층 | 2867553 | 1420 | 0.365 | 0.0142 | 0.72
2868962 | 지상 1층 | 지상 1층 | 2867553 | 1420 | 0.365 | 0.0142 | 0.72
2868963 | 지상 1층 | 지상 1층 | 2867553 | 1420 | 0.365 | 0.0142 | 0.72
2868964 | 지상 1층 | 지상 1층 | 2867553 | 1420 | 0.365 | 0.0142 | 0.72
2868965 | 지상 1층 | 지상 1층 | 2867553 | 1420 | 0.365 | 0.0142 | 0.72
2869490 | 지상 1층 | 지상 1층 | 2867553 | 2100 | 0.535 | 0.021 | 1.06
2870110 | 지상 1층 | 지상 1층 | 2870107 | 1125 | 0.29125 | 0.01125 | 0.5825
2870111 | 지상 1층 | 지상 1층 | 2870107 | 2025 | 0.51625 | 0.02025 | 1.0325
2870112 | 지상 1층 | 지상 1층 | 2870107 | 2100 | 0.535 | 0.021 | 1.06
2870113 | 지상 1층 | 지상 1층 | 2870107 | 1420 | 0.365 | 0.0142 | 0.72
2871055 | 지상 1층 | 지상 1층 | 2870107 | 2350 | 0.5975 | 0.0235 | 1.195
2871056 | 지상 1층 | 지상 1층 | 2870107 | 1125 | 0.29125 | 0.01125 | 0.5825
2871057 | 지상 1층 | 지상 1층 | 2870107 | 2100 | 0.535 | 0.021 | 1.06
2871145 | 지상 1층 | 지상 1층 | 2870107 | 2450 | 0.6225 | 0.0245 | 1.245
2871146 | 지상 1층 | 지상 1층 | 2870107 | 2350 | 0.5975 | 0.0235 | 1.195
2871147 | 지상 1층 | 지상 1층 | 2870107 | 2100 | 0.535 | 0.021 | 1.06
2871306 | 지상 1층 | 지상 1층 | 2870107 | 2450 | 0.6225 | 0.0245 | 1.245
2871307 | 지상 1층 | 지상 1층 | 2870107 | 2450 | 0.6225 | 0.0245 | 1.245
2871308 | 지상 1층 | 지상 1층 | 2870107 | 2100 | 0.535 | 0.021 | 1.06
2871481 | 지상 1층 | 지상 1층 | 2870107 | 2025 | 0.51625 | 0.02025 | 1.0325
2871482 | 지상 1층 | 지상 1층 | 2870107 | 2450 | 0.6225 | 0.0245 | 1.245
2871483 | 지상 1층 | 지상 1층 | 2870107 | 2100 | 0.535 | 0.021 | 1.06
2871586 | 지상 1층 | 지상 1층 | 2870107 | 1420 | 0.365 | 0.0142 | 0.72
2871587 | 지상 1층 | 지상 1층 | 2870107 | 2100 | 0.535 | 0.021 | 1.06
2871588 | 지상 1층 | 지상 1층 | 2870107 | 2025 | 0.51625 | 0.02025 | 1.0325
2871589 | 지상 1층 | 지상 1층 | 2870107 | 2450 | 0.6225 | 0.0245 | 1.245
2871590 | 지상 1층 | 지상 1층 | 2870107 | 2450 | 0.6225 | 0.0245 | 1.245
2871591 | 지상 1층 | 지상 1층 | 2870107 | 2350 | 0.5975 | 0.0235 | 1.195
2871592 | 지상 1층 | 지상 1층 | 2870107 | 1125 | 0.29125 | 0.01125 | 0.5825
2871593 | 지상 1층 | 지상 1층 | 2870107 | 1420 | 0.365 | 0.0142 | 0.72
2871594 | 지상 1층 | 지상 1층 | 2870107 | 1420 | 0.365 | 0.0142 | 0.72
2871595 | 지상 1층 | 지상 1층 | 2870107 | 1420 | 0.365 | 0.0142 | 0.72
2871596 | 지상 1층 | 지상 1층 | 2870107 | 1420 | 0.365 | 0.0142 | 0.72
2872004 | 지상 1층 | 지상 1층 | 2872001 | 1960 | 0.5 | 0.0196 | 1
2872006 | 지상 1층 | 지상 1층 | 2872001 | 2100 | 0.535 | 0.021 | 1.06
2872007 | 지상 1층 | 지상 1층 | 2872001 | 1420 | 0.365 | 0.0142 | 0.72
2873077 | 지상 1층 | 지상 1층 | 2872001 | 1420 | 0.365 | 0.0142 | 0.72
2873078 | 지상 1층 | 지상 1층 | 2872001 | 2100 | 0.535 | 0.021 | 1.06
2873079 | 지상 1층 | 지상 1층 | 2872001 | 925 | 0.24125 | 0.00925 | 0.4825
2873183 | 지상 1층 | 지상 1층 | 2872001 | 925 | 0.24125 | 0.00925 | 0.4825
2873184 | 지상 1층 | 지상 1층 | 2872001 | 1875 | 0.47875 | 0.01875 | 0.9575
2873185 | 지상 1층 | 지상 1층 | 2872001 | 1875 | 0.47875 | 0.01875 | 0.9575
2873186 | 지상 1층 | 지상 1층 | 2872001 | 2100 | 0.535 | 0.021 | 1.06
2873187 | 지상 1층 | 지상 1층 | 2872001 | 1420 | 0.365 | 0.0142 | 0.72
2873286 | 지상 1층 | 지상 1층 | 2872001 | 1875 | 0.47875 | 0.01875 | 0.9575
2873287 | 지상 1층 | 지상 1층 | 2872001 | 1975 | 0.50375 | 0.01975 | 1.0075
2873288 | 지상 1층 | 지상 1층 | 2872001 | 1975 | 0.50375 | 0.01975 | 1.0075
2873289 | 지상 1층 | 지상 1층 | 2872001 | 2100 | 0.535 | 0.021 | 1.06
2873290 | 지상 1층 | 지상 1층 | 2872001 | 1420 | 0.365 | 0.0142 | 0.72
2873426 | 지상 1층 | 지상 1층 | 2872001 | 1975 | 0.50375 | 0.01975 | 1.0075
2873428 | 지상 1층 | 지상 1층 | 2872001 | 950 | 0.2475 | 0.0095 | 0.495
2873429 | 지상 1층 | 지상 1층 | 2872001 | 2100 | 0.535 | 0.021 | 1.06
2873430 | 지상 1층 | 지상 1층 | 2872001 | 1420 | 0.365 | 0.0142 | 0.72
2873605 | 지상 1층 | 지상 1층 | 2872001 | 950 | 0.2475 | 0.0095 | 0.495
2873606 | 지상 1층 | 지상 1층 | 2872001 | 1865 | 0.47625 | 0.01865 | 0.9525
2873607 | 지상 1층 | 지상 1층 | 2872001 | 1865 | 0.47625 | 0.01865 | 0.9525
2873608 | 지상 1층 | 지상 1층 | 2872001 | 2100 | 0.535 | 0.021 | 1.06
2873609 | 지상 1층 | 지상 1층 | 2872001 | 1420 | 0.365 | 0.0142 | 0.72
2873752 | 지상 1층 | 지상 1층 | 2872001 | 1865 | 0.47625 | 0.01865 | 0.9525
2873753 | 지상 1층 | 지상 1층 | 2872001 | 1960 | 0.5 | 0.0196 | 1
2873754 | 지상 1층 | 지상 1층 | 2872001 | 1960 | 0.5 | 0.0196 | 1
2873755 | 지상 1층 | 지상 1층 | 2872001 | 2100 | 0.535 | 0.021 | 1.06
2873756 | 지상 1층 | 지상 1층 | 2872001 | 1420 | 0.365 | 0.0142 | 0.72
2874149 | 지상 1층 | 지상 1층 | 2874145 | 2275 | 0.57875 | 0.02275 | 1.1575
2874151 | 지상 1층 | 지상 1층 | 2874145 | 2100 | 0.535 | 0.021 | 1.06
2874152 | 지상 1층 | 지상 1층 | 2874145 | 1420 | 0.365 | 0.0142 | 0.72
2874849 | 지상 1층 | 지상 1층 | 2874145 | 925 | 0.24125 | 0.00925 | 0.4825
2874850 | 지상 1층 | 지상 1층 | 2874145 | 2199.97 | 0.559991 | 0.0219997 | 1.11998
2874851 | 지상 1층 | 지상 1층 | 2874145 | 2100 | 0.535 | 0.021 | 1.06
2874923 | 지상 1층 | 지상 1층 | 2874145 | 2199.97 | 0.559991 | 0.0219997 | 1.11998
2874925 | 지상 1층 | 지상 1층 | 2874145 | 2100 | 0.535 | 0.021 | 1.06
2875040 | 지상 1층 | 지상 1층 | 2874145 | 950 | 0.2475 | 0.0095 | 0.495
2875041 | 지상 1층 | 지상 1층 | 2874145 | 2275 | 0.57875 | 0.02275 | 1.1575
2875042 | 지상 1층 | 지상 1층 | 2874145 | 2100 | 0.535 | 0.021 | 1.06
2875139 | 지상 1층 | 지상 1층 | 2874145 | 1420 | 0.365 | 0.0142 | 0.72
2875140 | 지상 1층 | 지상 1층 | 2874145 | 2100 | 0.535 | 0.021 | 1.06
2875141 | 지상 1층 | 지상 1층 | 2874145 | 925 | 0.24125 | 0.00925 | 0.4825
2875142 | 지상 1층 | 지상 1층 | 2874145 | 2199.97 | 0.559991 | 0.0219997 | 1.11998
2875143 | 지상 1층 | 지상 1층 | 2874145 | 950 | 0.2475 | 0.0095 | 0.495
2875144 | 지상 1층 | 지상 1층 | 2874145 | 2275 | 0.57875 | 0.02275 | 1.1575
2875145 | 지상 1층 | 지상 1층 | 2874145 | 1420 | 0.365 | 0.0142 | 0.72
2875146 | 지상 1층 | 지상 1층 | 2874145 | 1420 | 0.365 | 0.0142 | 0.72
2875147 | 지상 1층 | 지상 1층 | 2874145 | 1420 | 0.365 | 0.0142 | 0.72
2875699 | 지상 1층 | 지상 1층 | 2875696 | 1304.97 | 0.336241 | 0.0130497 | 0.672483
2875702 | 지상 1층 | 지상 1층 | 2875696 | 1420 | 0.365 | 0.0142 | 0.72
2876422 | 지상 1층 | 지상 1층 | 2875696 | 925 | 0.24125 | 0.00925 | 0.4825
2876423 | 지상 1층 | 지상 1층 | 2875696 | 1450 | 0.3725 | 0.0145 | 0.745
2876424 | 지상 1층 | 지상 1층 | 2875696 | 2100 | 0.535 | 0.021 | 1.06
2876580 | 지상 1층 | 지상 1층 | 2875696 | 1450 | 0.3725 | 0.0145 | 0.745
2876581 | 지상 1층 | 지상 1층 | 2875696 | 1304.97 | 0.336241 | 0.0130497 | 0.672483
2876582 | 지상 1층 | 지상 1층 | 2875696 | 2100 | 0.535 | 0.021 | 1.06
2876778 | 지상 1층 | 지상 1층 | 2875696 | 2100 | 0.535 | 0.021 | 1.06
2876779 | 지상 1층 | 지상 1층 | 2875696 | 925 | 0.24125 | 0.00925 | 0.4825
2876780 | 지상 1층 | 지상 1층 | 2875696 | 1450 | 0.3725 | 0.0145 | 0.745
2876781 | 지상 1층 | 지상 1층 | 2875696 | 1304.97 | 0.336241 | 0.0130497 | 0.672483
2876782 | 지상 1층 | 지상 1층 | 2875696 | 1420 | 0.365 | 0.0142 | 0.72
2876783 | 지상 1층 | 지상 1층 | 2875696 | 1420 | 0.365 | 0.0142 | 0.72
2875830 | 지상 1층 | 지상 1층 | 2875827 | 692 | 0.183 | 0.00692 | 0.366
2875831 | 지상 1층 | 지상 1층 | 2875827 | 801.153 | 0.210288 | 0.00801153 | 0.420577
2875832 | 지상 1층 | 지상 1층 | 2875827 | 2100 | 0.535 | 0.021 | 1.06
2878095 | 지상 1층 | 지상 1층 | 2875827 | 1420 | 0.365 | 0.0142 | 0.72
2878097 | 지상 1층 | 지상 1층 | 2875827 | 801.153 | 0.210288 | 0.00801153 | 0.420577
2878167 | 지상 1층 | 지상 1층 | 2875827 | 801.153 | 0.210288 | 0.00801153 | 0.420577
2878169 | 지상 1층 | 지상 1층 | 2875827 | 950 | 0.2475 | 0.0095 | 0.495
2878170 | 지상 1층 | 지상 1층 | 2875827 | 2100 | 0.535 | 0.021 | 1.06
2878171 | 지상 1층 | 지상 1층 | 2875827 | 1420 | 0.365 | 0.0142 | 0.72
2878335 | 지상 1층 | 지상 1층 | 2875827 | 950 | 0.2475 | 0.0095 | 0.495
2878336 | 지상 1층 | 지상 1층 | 2875827 | 692 | 0.183 | 0.00692 | 0.366
2878337 | 지상 1층 | 지상 1층 | 2875827 | 692 | 0.183 | 0.00692 | 0.366
2878338 | 지상 1층 | 지상 1층 | 2875827 | 2100 | 0.535 | 0.021 | 1.06
2878339 | 지상 1층 | 지상 1층 | 2875827 | 1420 | 0.365 | 0.0142 | 0.72
2880754 | 지상 2층 | 지상 2층 | 2880752 | 1100 | 0.285 | 0.011 | 0.57
2880755 | 지상 2층 | 지상 2층 | 2880752 | 1100 | 0.285 | 0.011 | 0.57
2880756 | 지상 2층 | 지상 2층 | 2880752 | 850 | 0.2225 | 0.0085 | 0.435
2880757 | 지상 2층 | 지상 2층 | 2880752 | 1670 | 0.4275 | 0.0167 | 0.845
2880760 | 지상 2층 | 지상 2층 | 2880752 | 1670 | 0.4275 | 0.0167 | 0.845
2880761 | 지상 2층 | 지상 2층 | 2880752 | 600 | 0.16 | 0.006 | 0.3
2880762 | 지상 2층 | 지상 2층 | 2880752 | 1100 | 0.285 | 0.011 | 0.57
2880885 | 지상 2층 | 지상 2층 | 2880752 | 600 | 0.16 | 0.006 | 0.3
2880886 | 지상 2층 | 지상 2층 | 2880752 | 850 | 0.2225 | 0.0085 | 0.435
2880887 | 지상 2층 | 지상 2층 | 2880752 | 1100 | 0.285 | 0.011 | 0.57
2894519 | 지상 2층 | 지상 2층 | 2894516 | 943.75 | 0.245938 | 0.0094375 | 0.491875
2894520 | 지상 2층 | 지상 2층 | 2894516 | 903.75 | 0.235937 | 0.0090375 | 0.471875
2894521 | 지상 2층 | 지상 2층 | 2894516 | 650 | 0.1725 | 0.0065 | 0.335
2894522 | 지상 2층 | 지상 2층 | 2894516 | 1520 | 0.39 | 0.0152 | 0.77
2894888 | 지상 2층 | 지상 2층 | 2894516 | 903.75 | 0.235937 | 0.0090375 | 0.471875
2894889 | 지상 2층 | 지상 2층 | 2894516 | 818.75 | 0.214688 | 0.0081875 | 0.429375
2894890 | 지상 2층 | 지상 2층 | 2894516 | 650 | 0.1725 | 0.0065 | 0.335
2895008 | 지상 2층 | 지상 2층 | 2894516 | 818.75 | 0.214688 | 0.0081875 | 0.429375
2895009 | 지상 2층 | 지상 2층 | 2894516 | 818.75 | 0.214688 | 0.0081875 | 0.429375
2895010 | 지상 2층 | 지상 2층 | 2894516 | 650 | 0.1725 | 0.0065 | 0.335
2895113 | 지상 2층 | 지상 2층 | 2894516 | 818.75 | 0.214688 | 0.0081875 | 0.429375
2895114 | 지상 2층 | 지상 2층 | 2894516 | 818.75 | 0.214688 | 0.0081875 | 0.429375
2895115 | 지상 2층 | 지상 2층 | 2894516 | 650 | 0.1725 | 0.0065 | 0.335
2895239 | 지상 2층 | 지상 2층 | 2894516 | 818.75 | 0.214688 | 0.0081875 | 0.429375
2895240 | 지상 2층 | 지상 2층 | 2894516 | 818.75 | 0.214688 | 0.0081875 | 0.429375
2895241 | 지상 2층 | 지상 2층 | 2894516 | 650 | 0.1725 | 0.0065 | 0.335
2895337 | 지상 2층 | 지상 2층 | 2894516 | 818.75 | 0.214688 | 0.0081875 | 0.429375
2895338 | 지상 2층 | 지상 2층 | 2894516 | 818.75 | 0.214688 | 0.0081875 | 0.429375
2895339 | 지상 2층 | 지상 2층 | 2894516 | 650 | 0.1725 | 0.0065 | 0.335
2895427 | 지상 2층 | 지상 2층 | 2894516 | 818.75 | 0.214688 | 0.0081875 | 0.429375
2895428 | 지상 2층 | 지상 2층 | 2894516 | 818.75 | 0.214688 | 0.0081875 | 0.429375
2895429 | 지상 2층 | 지상 2층 | 2894516 | 650 | 0.1725 | 0.0065 | 0.335
2895532 | 지상 2층 | 지상 2층 | 2894516 | 818.75 | 0.214688 | 0.0081875 | 0.429375
2895533 | 지상 2층 | 지상 2층 | 2894516 | 943.75 | 0.245938 | 0.0094375 | 0.491875
2895534 | 지상 2층 | 지상 2층 | 2894516 | 650 | 0.1725 | 0.0065 | 0.335
2895679 | 지상 2층 | 지상 2층 | 2894516 | 1520 | 0.39 | 0.0152 | 0.77
2895680 | 지상 2층 | 지상 2층 | 2894516 | 600 | 0.16 | 0.006 | 0.3
2895681 | 지상 2층 | 지상 2층 | 2894516 | 903.75 | 0.235937 | 0.0090375 | 0.471875
2895682 | 지상 2층 | 지상 2층 | 2894516 | 818.75 | 0.214688 | 0.0081875 | 0.429375
2895683 | 지상 2층 | 지상 2층 | 2894516 | 818.75 | 0.214688 | 0.0081875 | 0.429375
2895684 | 지상 2층 | 지상 2층 | 2894516 | 818.75 | 0.214688 | 0.0081875 | 0.429375
2895685 | 지상 2층 | 지상 2층 | 2894516 | 818.75 | 0.214688 | 0.0081875 | 0.429375
2895686 | 지상 2층 | 지상 2층 | 2894516 | 818.75 | 0.214688 | 0.0081875 | 0.429375
2895687 | 지상 2층 | 지상 2층 | 2894516 | 818.75 | 0.214688 | 0.0081875 | 0.429375
2895688 | 지상 2층 | 지상 2층 | 2894516 | 943.75 | 0.245938 | 0.0094375 | 0.491875
2895689 | 지상 2층 | 지상 2층 | 2894516 | 1520 | 0.39 | 0.0152 | 0.77
2895690 | 지상 2층 | 지상 2층 | 2894516 | 1520 | 0.39 | 0.0152 | 0.77
2895691 | 지상 2층 | 지상 2층 | 2894516 | 1520 | 0.39 | 0.0152 | 0.77
2895692 | 지상 2층 | 지상 2층 | 2894516 | 1520 | 0.39 | 0.0152 | 0.77
2895693 | 지상 2층 | 지상 2층 | 2894516 | 1520 | 0.39 | 0.0152 | 0.77
2895694 | 지상 2층 | 지상 2층 | 2894516 | 1520 | 0.39 | 0.0152 | 0.77
2895695 | 지상 2층 | 지상 2층 | 2894516 | 1520 | 0.39 | 0.0152 | 0.77
2895826 | 지상 2층 | 지상 2층 | 2894516 | 600 | 0.16 | 0.006 | 0.3
2895827 | 지상 2층 | 지상 2층 | 2894516 | 350 | 0.0975 | 0.0035 | 0.175
2895828 | 지상 2층 | 지상 2층 | 2894516 | 903.75 | 0.235937 | 0.0090375 | 0.471875
2895829 | 지상 2층 | 지상 2층 | 2894516 | 818.75 | 0.214688 | 0.0081875 | 0.429375
2895830 | 지상 2층 | 지상 2층 | 2894516 | 818.75 | 0.214688 | 0.0081875 | 0.429375
2895831 | 지상 2층 | 지상 2층 | 2894516 | 818.75 | 0.214688 | 0.0081875 | 0.429375
2895832 | 지상 2층 | 지상 2층 | 2894516 | 818.75 | 0.214688 | 0.0081875 | 0.429375
2895833 | 지상 2층 | 지상 2층 | 2894516 | 818.75 | 0.214688 | 0.0081875 | 0.429375
2895834 | 지상 2층 | 지상 2층 | 2894516 | 818.75 | 0.214688 | 0.0081875 | 0.429375
2895835 | 지상 2층 | 지상 2층 | 2894516 | 943.75 | 0.245938 | 0.0094375 | 0.491875
2895836 | 지상 2층 | 지상 2층 | 2894516 | 600 | 0.16 | 0.006 | 0.3
2895837 | 지상 2층 | 지상 2층 | 2894516 | 600 | 0.16 | 0.006 | 0.3
2895838 | 지상 2층 | 지상 2층 | 2894516 | 600 | 0.16 | 0.006 | 0.3
2895839 | 지상 2층 | 지상 2층 | 2894516 | 600 | 0.16 | 0.006 | 0.3
2895840 | 지상 2층 | 지상 2층 | 2894516 | 600 | 0.16 | 0.006 | 0.3
2895841 | 지상 2층 | 지상 2층 | 2894516 | 600 | 0.16 | 0.006 | 0.3
2895842 | 지상 2층 | 지상 2층 | 2894516 | 600 | 0.16 | 0.006 | 0.3
2895974 | 지상 2층 | 지상 2층 | 2894516 | 350 | 0.0975 | 0.0035 | 0.175
2895975 | 지상 2층 | 지상 2층 | 2894516 | 650 | 0.1725 | 0.0065 | 0.335
2895976 | 지상 2층 | 지상 2층 | 2894516 | 903.75 | 0.235937 | 0.0090375 | 0.471875
2895977 | 지상 2층 | 지상 2층 | 2894516 | 818.75 | 0.214688 | 0.0081875 | 0.429375
2895978 | 지상 2층 | 지상 2층 | 2894516 | 818.75 | 0.214688 | 0.0081875 | 0.429375
2895979 | 지상 2층 | 지상 2층 | 2894516 | 818.75 | 0.214688 | 0.0081875 | 0.429375
2895980 | 지상 2층 | 지상 2층 | 2894516 | 818.75 | 0.214688 | 0.0081875 | 0.429375
2895981 | 지상 2층 | 지상 2층 | 2894516 | 818.75 | 0.214688 | 0.0081875 | 0.429375
2895982 | 지상 2층 | 지상 2층 | 2894516 | 818.75 | 0.214688 | 0.0081875 | 0.429375
2895983 | 지상 2층 | 지상 2층 | 2894516 | 943.75 | 0.245938 | 0.0094375 | 0.491875
2895984 | 지상 2층 | 지상 2층 | 2894516 | 350 | 0.0975 | 0.0035 | 0.175
2895985 | 지상 2층 | 지상 2층 | 2894516 | 350 | 0.0975 | 0.0035 | 0.175
2895986 | 지상 2층 | 지상 2층 | 2894516 | 350 | 0.0975 | 0.0035 | 0.175
2895987 | 지상 2층 | 지상 2층 | 2894516 | 350 | 0.0975 | 0.0035 | 0.175
2895988 | 지상 2층 | 지상 2층 | 2894516 | 350 | 0.0975 | 0.0035 | 0.175
2895989 | 지상 2층 | 지상 2층 | 2894516 | 350 | 0.0975 | 0.0035 | 0.175
2895990 | 지상 2층 | 지상 2층 | 2894516 | 350 | 0.0975 | 0.0035 | 0.175
2897087 | 지상 2층 | 지상 2층 | 2897084 | 868.767 | 0.227192 | 0.00868767 | 0.454384
2897088 | 지상 2층 | 지상 2층 | 2897084 | 818.733 | 0.214683 | 0.00818733 | 0.429366
2897089 | 지상 2층 | 지상 2층 | 2897084 | 650 | 0.1725 | 0.0065 | 0.335
2897090 | 지상 2층 | 지상 2층 | 2897084 | 1520 | 0.39 | 0.0152 | 0.77
2897497 | 지상 2층 | 지상 2층 | 2897084 | 818.733 | 0.214683 | 0.00818733 | 0.429366
2897498 | 지상 2층 | 지상 2층 | 2897084 | 743.75 | 0.195938 | 0.0074375 | 0.391875
2897499 | 지상 2층 | 지상 2층 | 2897084 | 650 | 0.1725 | 0.0065 | 0.335
2897573 | 지상 2층 | 지상 2층 | 2897084 | 1520 | 0.39 | 0.0152 | 0.77
2897574 | 지상 2층 | 지상 2층 | 2897084 | 600 | 0.16 | 0.006 | 0.3
2897575 | 지상 2층 | 지상 2층 | 2897084 | 818.733 | 0.214683 | 0.00818733 | 0.429366
2897576 | 지상 2층 | 지상 2층 | 2897084 | 743.75 | 0.195938 | 0.0074375 | 0.391875
2897577 | 지상 2층 | 지상 2층 | 2897084 | 1520 | 0.39 | 0.0152 | 0.77
2897635 | 지상 2층 | 지상 2층 | 2897084 | 743.75 | 0.195938 | 0.0074375 | 0.391875
2897636 | 지상 2층 | 지상 2층 | 2897084 | 743.75 | 0.195938 | 0.0074375 | 0.391875
2897637 | 지상 2층 | 지상 2층 | 2897084 | 743.75 | 0.195938 | 0.0074375 | 0.391875
2897638 | 지상 2층 | 지상 2층 | 2897084 | 650 | 0.1725 | 0.0065 | 0.335
2897639 | 지상 2층 | 지상 2층 | 2897084 | 1520 | 0.39 | 0.0152 | 0.77
2897724 | 지상 2층 | 지상 2층 | 2897084 | 743.75 | 0.195938 | 0.0074375 | 0.391875
2897725 | 지상 2층 | 지상 2층 | 2897084 | 743.75 | 0.195938 | 0.0074375 | 0.391875
2897726 | 지상 2층 | 지상 2층 | 2897084 | 743.75 | 0.195938 | 0.0074375 | 0.391875
2897727 | 지상 2층 | 지상 2층 | 2897084 | 650 | 0.1725 | 0.0065 | 0.335
2897728 | 지상 2층 | 지상 2층 | 2897084 | 1520 | 0.39 | 0.0152 | 0.77
2897824 | 지상 2층 | 지상 2층 | 2897084 | 743.75 | 0.195938 | 0.0074375 | 0.391875
2897825 | 지상 2층 | 지상 2층 | 2897084 | 743.75 | 0.195938 | 0.0074375 | 0.391875
2897826 | 지상 2층 | 지상 2층 | 2897084 | 743.75 | 0.195938 | 0.0074375 | 0.391875
2897827 | 지상 2층 | 지상 2층 | 2897084 | 650 | 0.1725 | 0.0065 | 0.335
2897828 | 지상 2층 | 지상 2층 | 2897084 | 1520 | 0.39 | 0.0152 | 0.77
2897913 | 지상 2층 | 지상 2층 | 2897084 | 743.75 | 0.195938 | 0.0074375 | 0.391875
2897914 | 지상 2층 | 지상 2층 | 2897084 | 743.75 | 0.195938 | 0.0074375 | 0.391875
2897915 | 지상 2층 | 지상 2층 | 2897084 | 743.75 | 0.195938 | 0.0074375 | 0.391875
2897916 | 지상 2층 | 지상 2층 | 2897084 | 650 | 0.1725 | 0.0065 | 0.335
2897917 | 지상 2층 | 지상 2층 | 2897084 | 1520 | 0.39 | 0.0152 | 0.77
2898003 | 지상 2층 | 지상 2층 | 2897084 | 743.75 | 0.195938 | 0.0074375 | 0.391875
2898004 | 지상 2층 | 지상 2층 | 2897084 | 743.75 | 0.195938 | 0.0074375 | 0.391875
2898005 | 지상 2층 | 지상 2층 | 2897084 | 743.75 | 0.195938 | 0.0074375 | 0.391875
2898006 | 지상 2층 | 지상 2층 | 2897084 | 650 | 0.1725 | 0.0065 | 0.335
2898007 | 지상 2층 | 지상 2층 | 2897084 | 1520 | 0.39 | 0.0152 | 0.77
2898097 | 지상 2층 | 지상 2층 | 2897084 | 743.75 | 0.195938 | 0.0074375 | 0.391875
2898098 | 지상 2층 | 지상 2층 | 2897084 | 868.767 | 0.227192 | 0.00868767 | 0.454384
2898099 | 지상 2층 | 지상 2층 | 2897084 | 868.767 | 0.227192 | 0.00868767 | 0.454384
2898100 | 지상 2층 | 지상 2층 | 2897084 | 650 | 0.1725 | 0.0065 | 0.335
2898101 | 지상 2층 | 지상 2층 | 2897084 | 1520 | 0.39 | 0.0152 | 0.77
2898287 | 지상 2층 | 지상 2층 | 2897084 | 600 | 0.16 | 0.006 | 0.3
2898288 | 지상 2층 | 지상 2층 | 2897084 | 350 | 0.0975 | 0.0035 | 0.175
2898289 | 지상 2층 | 지상 2층 | 2897084 | 818.733 | 0.214683 | 0.00818733 | 0.429366
2898290 | 지상 2층 | 지상 2층 | 2897084 | 743.75 | 0.195938 | 0.0074375 | 0.391875
2898291 | 지상 2층 | 지상 2층 | 2897084 | 743.75 | 0.195938 | 0.0074375 | 0.391875
2898292 | 지상 2층 | 지상 2층 | 2897084 | 743.75 | 0.195938 | 0.0074375 | 0.391875
2898293 | 지상 2층 | 지상 2층 | 2897084 | 743.75 | 0.195938 | 0.0074375 | 0.391875
2898294 | 지상 2층 | 지상 2층 | 2897084 | 743.75 | 0.195938 | 0.0074375 | 0.391875
2898295 | 지상 2층 | 지상 2층 | 2897084 | 743.75 | 0.195938 | 0.0074375 | 0.391875
2898296 | 지상 2층 | 지상 2층 | 2897084 | 868.767 | 0.227192 | 0.00868767 | 0.454384
2898297 | 지상 2층 | 지상 2층 | 2897084 | 600 | 0.16 | 0.006 | 0.3
2898298 | 지상 2층 | 지상 2층 | 2897084 | 600 | 0.16 | 0.006 | 0.3
2898299 | 지상 2층 | 지상 2층 | 2897084 | 600 | 0.16 | 0.006 | 0.3
2898300 | 지상 2층 | 지상 2층 | 2897084 | 600 | 0.16 | 0.006 | 0.3
2898301 | 지상 2층 | 지상 2층 | 2897084 | 600 | 0.16 | 0.006 | 0.3
2898302 | 지상 2층 | 지상 2층 | 2897084 | 600 | 0.16 | 0.006 | 0.3
2898303 | 지상 2층 | 지상 2층 | 2897084 | 600 | 0.16 | 0.006 | 0.3
2898359 | 지상 2층 | 지상 2층 | 2897084 | 350 | 0.0975 | 0.0035 | 0.175
2898360 | 지상 2층 | 지상 2층 | 2897084 | 650 | 0.1725 | 0.0065 | 0.335
2898361 | 지상 2층 | 지상 2층 | 2897084 | 818.733 | 0.214683 | 0.00818733 | 0.429366
2898362 | 지상 2층 | 지상 2층 | 2897084 | 743.75 | 0.195938 | 0.0074375 | 0.391875
2898363 | 지상 2층 | 지상 2층 | 2897084 | 743.75 | 0.195938 | 0.0074375 | 0.391875
2898364 | 지상 2층 | 지상 2층 | 2897084 | 743.75 | 0.195938 | 0.0074375 | 0.391875
2898365 | 지상 2층 | 지상 2층 | 2897084 | 743.75 | 0.195938 | 0.0074375 | 0.391875
2898366 | 지상 2층 | 지상 2층 | 2897084 | 743.75 | 0.195938 | 0.0074375 | 0.391875
2898367 | 지상 2층 | 지상 2층 | 2897084 | 743.75 | 0.195938 | 0.0074375 | 0.391875
2898368 | 지상 2층 | 지상 2층 | 2897084 | 868.767 | 0.227192 | 0.00868767 | 0.454384
2898369 | 지상 2층 | 지상 2층 | 2897084 | 350 | 0.0975 | 0.0035 | 0.175
2898370 | 지상 2층 | 지상 2층 | 2897084 | 350 | 0.0975 | 0.0035 | 0.175
2898371 | 지상 2층 | 지상 2층 | 2897084 | 350 | 0.0975 | 0.0035 | 0.175
2898372 | 지상 2층 | 지상 2층 | 2897084 | 350 | 0.0975 | 0.0035 | 0.175
2898373 | 지상 2층 | 지상 2층 | 2897084 | 350 | 0.0975 | 0.0035 | 0.175
2898374 | 지상 2층 | 지상 2층 | 2897084 | 350 | 0.0975 | 0.0035 | 0.175
2898375 | 지상 2층 | 지상 2층 | 2897084 | 350 | 0.0975 | 0.0035 | 0.175
2898539 | 지상 2층 | 지상 2층 | 2898536 | 856.25 | 0.224062 | 0.0085625 | 0.448125
2898540 | 지상 2층 | 지상 2층 | 2898536 | 806.25 | 0.211563 | 0.0080625 | 0.423125
2898541 | 지상 2층 | 지상 2층 | 2898536 | 650 | 0.1725 | 0.0065 | 0.335
2898542 | 지상 2층 | 지상 2층 | 2898536 | 1520 | 0.39 | 0.0152 | 0.77
2898846 | 지상 2층 | 지상 2층 | 2898536 | 806.25 | 0.211563 | 0.0080625 | 0.423125
2898847 | 지상 2층 | 지상 2층 | 2898536 | 731.25 | 0.192812 | 0.0073125 | 0.385625
2898848 | 지상 2층 | 지상 2층 | 2898536 | 650 | 0.1725 | 0.0065 | 0.335
2898887 | 지상 2층 | 지상 2층 | 2898536 | 731.25 | 0.192812 | 0.0073125 | 0.385625
2898888 | 지상 2층 | 지상 2층 | 2898536 | 731.25 | 0.192812 | 0.0073125 | 0.385625
2898889 | 지상 2층 | 지상 2층 | 2898536 | 650 | 0.1725 | 0.0065 | 0.335
2898964 | 지상 2층 | 지상 2층 | 2898536 | 731.25 | 0.192812 | 0.0073125 | 0.385625
2898965 | 지상 2층 | 지상 2층 | 2898536 | 731.25 | 0.192812 | 0.0073125 | 0.385625
2898966 | 지상 2층 | 지상 2층 | 2898536 | 650 | 0.1725 | 0.0065 | 0.335
2899045 | 지상 2층 | 지상 2층 | 2898536 | 731.25 | 0.192812 | 0.0073125 | 0.385625
2899046 | 지상 2층 | 지상 2층 | 2898536 | 731.25 | 0.192812 | 0.0073125 | 0.385625
2899047 | 지상 2층 | 지상 2층 | 2898536 | 650 | 0.1725 | 0.0065 | 0.335
2899140 | 지상 2층 | 지상 2층 | 2898536 | 731.25 | 0.192812 | 0.0073125 | 0.385625
2899141 | 지상 2층 | 지상 2층 | 2898536 | 731.25 | 0.192812 | 0.0073125 | 0.385625
2899142 | 지상 2층 | 지상 2층 | 2898536 | 650 | 0.1725 | 0.0065 | 0.335
2899235 | 지상 2층 | 지상 2층 | 2898536 | 731.25 | 0.192812 | 0.0073125 | 0.385625
2899236 | 지상 2층 | 지상 2층 | 2898536 | 731.25 | 0.192812 | 0.0073125 | 0.385625
2899237 | 지상 2층 | 지상 2층 | 2898536 | 650 | 0.1725 | 0.0065 | 0.335
2899412 | 지상 2층 | 지상 2층 | 2898536 | 731.25 | 0.192812 | 0.0073125 | 0.385625
2899413 | 지상 2층 | 지상 2층 | 2898536 | 856.25 | 0.224062 | 0.0085625 | 0.448125
2899414 | 지상 2층 | 지상 2층 | 2898536 | 650 | 0.1725 | 0.0065 | 0.335
2899584 | 지상 2층 | 지상 2층 | 2898536 | 1520 | 0.39 | 0.0152 | 0.77
2899585 | 지상 2층 | 지상 2층 | 2898536 | 600 | 0.16 | 0.006 | 0.3
2899586 | 지상 2층 | 지상 2층 | 2898536 | 806.25 | 0.211563 | 0.0080625 | 0.423125
2899587 | 지상 2층 | 지상 2층 | 2898536 | 731.25 | 0.192812 | 0.0073125 | 0.385625
2899588 | 지상 2층 | 지상 2층 | 2898536 | 731.25 | 0.192812 | 0.0073125 | 0.385625
2899589 | 지상 2층 | 지상 2층 | 2898536 | 731.25 | 0.192812 | 0.0073125 | 0.385625
2899590 | 지상 2층 | 지상 2층 | 2898536 | 731.25 | 0.192812 | 0.0073125 | 0.385625
2899591 | 지상 2층 | 지상 2층 | 2898536 | 731.25 | 0.192812 | 0.0073125 | 0.385625
2899592 | 지상 2층 | 지상 2층 | 2898536 | 731.25 | 0.192812 | 0.0073125 | 0.385625
2899593 | 지상 2층 | 지상 2층 | 2898536 | 856.25 | 0.224062 | 0.0085625 | 0.448125
2899594 | 지상 2층 | 지상 2층 | 2898536 | 1520 | 0.39 | 0.0152 | 0.77
2899595 | 지상 2층 | 지상 2층 | 2898536 | 1520 | 0.39 | 0.0152 | 0.77
2899596 | 지상 2층 | 지상 2층 | 2898536 | 1520 | 0.39 | 0.0152 | 0.77
2899597 | 지상 2층 | 지상 2층 | 2898536 | 1520 | 0.39 | 0.0152 | 0.77
2899598 | 지상 2층 | 지상 2층 | 2898536 | 1520 | 0.39 | 0.0152 | 0.77
2899599 | 지상 2층 | 지상 2층 | 2898536 | 1520 | 0.39 | 0.0152 | 0.77
2899600 | 지상 2층 | 지상 2층 | 2898536 | 1520 | 0.39 | 0.0152 | 0.77
2899668 | 지상 2층 | 지상 2층 | 2898536 | 600 | 0.16 | 0.006 | 0.3
2899669 | 지상 2층 | 지상 2층 | 2898536 | 350 | 0.0975 | 0.0035 | 0.175
2899670 | 지상 2층 | 지상 2층 | 2898536 | 806.25 | 0.211563 | 0.0080625 | 0.423125
2899671 | 지상 2층 | 지상 2층 | 2898536 | 731.25 | 0.192812 | 0.0073125 | 0.385625
2899672 | 지상 2층 | 지상 2층 | 2898536 | 731.25 | 0.192812 | 0.0073125 | 0.385625
2899673 | 지상 2층 | 지상 2층 | 2898536 | 731.25 | 0.192812 | 0.0073125 | 0.385625
2899674 | 지상 2층 | 지상 2층 | 2898536 | 731.25 | 0.192812 | 0.0073125 | 0.385625
2899675 | 지상 2층 | 지상 2층 | 2898536 | 731.25 | 0.192812 | 0.0073125 | 0.385625
2899676 | 지상 2층 | 지상 2층 | 2898536 | 731.25 | 0.192812 | 0.0073125 | 0.385625
2899677 | 지상 2층 | 지상 2층 | 2898536 | 856.25 | 0.224062 | 0.0085625 | 0.448125
2899678 | 지상 2층 | 지상 2층 | 2898536 | 600 | 0.16 | 0.006 | 0.3
2899679 | 지상 2층 | 지상 2층 | 2898536 | 600 | 0.16 | 0.006 | 0.3
2899680 | 지상 2층 | 지상 2층 | 2898536 | 600 | 0.16 | 0.006 | 0.3
2899681 | 지상 2층 | 지상 2층 | 2898536 | 600 | 0.16 | 0.006 | 0.3
2899682 | 지상 2층 | 지상 2층 | 2898536 | 600 | 0.16 | 0.006 | 0.3
2899683 | 지상 2층 | 지상 2층 | 2898536 | 600 | 0.16 | 0.006 | 0.3
2899684 | 지상 2층 | 지상 2층 | 2898536 | 600 | 0.16 | 0.006 | 0.3
2899762 | 지상 2층 | 지상 2층 | 2898536 | 350 | 0.0975 | 0.0035 | 0.175
2899763 | 지상 2층 | 지상 2층 | 2898536 | 650 | 0.1725 | 0.0065 | 0.335
2899764 | 지상 2층 | 지상 2층 | 2898536 | 806.25 | 0.211563 | 0.0080625 | 0.423125
2899765 | 지상 2층 | 지상 2층 | 2898536 | 731.25 | 0.192812 | 0.0073125 | 0.385625
2899766 | 지상 2층 | 지상 2층 | 2898536 | 731.25 | 0.192812 | 0.0073125 | 0.385625
2899767 | 지상 2층 | 지상 2층 | 2898536 | 731.25 | 0.192812 | 0.0073125 | 0.385625
2899768 | 지상 2층 | 지상 2층 | 2898536 | 731.25 | 0.192812 | 0.0073125 | 0.385625
2899769 | 지상 2층 | 지상 2층 | 2898536 | 731.25 | 0.192812 | 0.0073125 | 0.385625
2899770 | 지상 2층 | 지상 2층 | 2898536 | 731.25 | 0.192812 | 0.0073125 | 0.385625
2899771 | 지상 2층 | 지상 2층 | 2898536 | 856.25 | 0.224062 | 0.0085625 | 0.448125
2899772 | 지상 2층 | 지상 2층 | 2898536 | 350 | 0.0975 | 0.0035 | 0.175
2899773 | 지상 2층 | 지상 2층 | 2898536 | 350 | 0.0975 | 0.0035 | 0.175
2899774 | 지상 2층 | 지상 2층 | 2898536 | 350 | 0.0975 | 0.0035 | 0.175
2899775 | 지상 2층 | 지상 2층 | 2898536 | 350 | 0.0975 | 0.0035 | 0.175
2899776 | 지상 2층 | 지상 2층 | 2898536 | 350 | 0.0975 | 0.0035 | 0.175
2899777 | 지상 2층 | 지상 2층 | 2898536 | 350 | 0.0975 | 0.0035 | 0.175
2899778 | 지상 2층 | 지상 2층 | 2898536 | 350 | 0.0975 | 0.0035 | 0.175
2900186 | 지상 2층 | 지상 2층 | 2900183 | 678.571 | 0.179643 | 0.00678571 | 0.359286
2900187 | 지상 2층 | 지상 2층 | 2900183 | 760.571 | 0.200143 | 0.00760571 | 0.400286
2900188 | 지상 2층 | 지상 2층 | 2900183 | 650 | 0.1725 | 0.0065 | 0.335
2900189 | 지상 2층 | 지상 2층 | 2900183 | 1520 | 0.39 | 0.0152 | 0.77
2900422 | 지상 2층 | 지상 2층 | 2900183 | 760.571 | 0.200143 | 0.00760571 | 0.400286
2900423 | 지상 2층 | 지상 2층 | 2900183 | 703.571 | 0.185893 | 0.00703571 | 0.371786
2900424 | 지상 2층 | 지상 2층 | 2900183 | 650 | 0.1725 | 0.0065 | 0.335
2900494 | 지상 2층 | 지상 2층 | 2900183 | 703.571 | 0.185893 | 0.00703571 | 0.371786
2900495 | 지상 2층 | 지상 2층 | 2900183 | 703.571 | 0.185893 | 0.00703571 | 0.371786
2900496 | 지상 2층 | 지상 2층 | 2900183 | 650 | 0.1725 | 0.0065 | 0.335
2900575 | 지상 2층 | 지상 2층 | 2900183 | 703.571 | 0.185893 | 0.00703571 | 0.371786
2900576 | 지상 2층 | 지상 2층 | 2900183 | 703.571 | 0.185893 | 0.00703571 | 0.371786
2900577 | 지상 2층 | 지상 2층 | 2900183 | 650 | 0.1725 | 0.0065 | 0.335
2900664 | 지상 2층 | 지상 2층 | 2900183 | 703.571 | 0.185893 | 0.00703571 | 0.371786
2900665 | 지상 2층 | 지상 2층 | 2900183 | 703.571 | 0.185893 | 0.00703571 | 0.371786
2900666 | 지상 2층 | 지상 2층 | 2900183 | 650 | 0.1725 | 0.0065 | 0.335
2900751 | 지상 2층 | 지상 2층 | 2900183 | 1520 | 0.39 | 0.0152 | 0.77
2900752 | 지상 2층 | 지상 2층 | 2900183 | 600 | 0.16 | 0.006 | 0.3
2900753 | 지상 2층 | 지상 2층 | 2900183 | 760.571 | 0.200143 | 0.00760571 | 0.400286
2900754 | 지상 2층 | 지상 2층 | 2900183 | 703.571 | 0.185893 | 0.00703571 | 0.371786
2900755 | 지상 2층 | 지상 2층 | 2900183 | 703.571 | 0.185893 | 0.00703571 | 0.371786
2900756 | 지상 2층 | 지상 2층 | 2900183 | 703.571 | 0.185893 | 0.00703571 | 0.371786
2900757 | 지상 2층 | 지상 2층 | 2900183 | 703.571 | 0.185893 | 0.00703571 | 0.371786
2900758 | 지상 2층 | 지상 2층 | 2900183 | 1520 | 0.39 | 0.0152 | 0.77
2900759 | 지상 2층 | 지상 2층 | 2900183 | 1520 | 0.39 | 0.0152 | 0.77
2900760 | 지상 2층 | 지상 2층 | 2900183 | 1520 | 0.39 | 0.0152 | 0.77
2900761 | 지상 2층 | 지상 2층 | 2900183 | 1520 | 0.39 | 0.0152 | 0.77
2900822 | 지상 2층 | 지상 2층 | 2900183 | 703.571 | 0.185893 | 0.00703571 | 0.371786
2900823 | 지상 2층 | 지상 2층 | 2900183 | 703.571 | 0.185893 | 0.00703571 | 0.371786
2900824 | 지상 2층 | 지상 2층 | 2900183 | 703.571 | 0.185893 | 0.00703571 | 0.371786
2900825 | 지상 2층 | 지상 2층 | 2900183 | 650 | 0.1725 | 0.0065 | 0.335
2900826 | 지상 2층 | 지상 2층 | 2900183 | 1520 | 0.39 | 0.0152 | 0.77
2900902 | 지상 2층 | 지상 2층 | 2900183 | 703.571 | 0.185893 | 0.00703571 | 0.371786
2900903 | 지상 2층 | 지상 2층 | 2900183 | 678.571 | 0.179643 | 0.00678571 | 0.359286
2900904 | 지상 2층 | 지상 2층 | 2900183 | 678.571 | 0.179643 | 0.00678571 | 0.359286
2900905 | 지상 2층 | 지상 2층 | 2900183 | 650 | 0.1725 | 0.0065 | 0.335
2900906 | 지상 2층 | 지상 2층 | 2900183 | 1520 | 0.39 | 0.0152 | 0.77
2900982 | 지상 2층 | 지상 2층 | 2900183 | 600 | 0.16 | 0.006 | 0.3
2900983 | 지상 2층 | 지상 2층 | 2900183 | 350 | 0.0975 | 0.0035 | 0.175
2900984 | 지상 2층 | 지상 2층 | 2900183 | 760.571 | 0.200143 | 0.00760571 | 0.400286
2900985 | 지상 2층 | 지상 2층 | 2900183 | 703.571 | 0.185893 | 0.00703571 | 0.371786
2900986 | 지상 2층 | 지상 2층 | 2900183 | 703.571 | 0.185893 | 0.00703571 | 0.371786
2900987 | 지상 2층 | 지상 2층 | 2900183 | 703.571 | 0.185893 | 0.00703571 | 0.371786
2900988 | 지상 2층 | 지상 2층 | 2900183 | 703.571 | 0.185893 | 0.00703571 | 0.371786
2900989 | 지상 2층 | 지상 2층 | 2900183 | 703.571 | 0.185893 | 0.00703571 | 0.371786
2900990 | 지상 2층 | 지상 2층 | 2900183 | 678.571 | 0.179643 | 0.00678571 | 0.359286
2900991 | 지상 2층 | 지상 2층 | 2900183 | 600 | 0.16 | 0.006 | 0.3
2900992 | 지상 2층 | 지상 2층 | 2900183 | 600 | 0.16 | 0.006 | 0.3
2900993 | 지상 2층 | 지상 2층 | 2900183 | 600 | 0.16 | 0.006 | 0.3
2900994 | 지상 2층 | 지상 2층 | 2900183 | 600 | 0.16 | 0.006 | 0.3
2900995 | 지상 2층 | 지상 2층 | 2900183 | 600 | 0.16 | 0.006 | 0.3
2900996 | 지상 2층 | 지상 2층 | 2900183 | 600 | 0.16 | 0.006 | 0.3
2901055 | 지상 2층 | 지상 2층 | 2900183 | 350 | 0.0975 | 0.0035 | 0.175
2901056 | 지상 2층 | 지상 2층 | 2900183 | 650 | 0.1725 | 0.0065 | 0.335
2901057 | 지상 2층 | 지상 2층 | 2900183 | 760.571 | 0.200143 | 0.00760571 | 0.400286
2901058 | 지상 2층 | 지상 2층 | 2900183 | 703.571 | 0.185893 | 0.00703571 | 0.371786
2901059 | 지상 2층 | 지상 2층 | 2900183 | 703.571 | 0.185893 | 0.00703571 | 0.371786
2901060 | 지상 2층 | 지상 2층 | 2900183 | 703.571 | 0.185893 | 0.00703571 | 0.371786
2901061 | 지상 2층 | 지상 2층 | 2900183 | 703.571 | 0.185893 | 0.00703571 | 0.371786
2901062 | 지상 2층 | 지상 2층 | 2900183 | 703.571 | 0.185893 | 0.00703571 | 0.371786
2901063 | 지상 2층 | 지상 2층 | 2900183 | 678.571 | 0.179643 | 0.00678571 | 0.359286
2901064 | 지상 2층 | 지상 2층 | 2900183 | 350 | 0.0975 | 0.0035 | 0.175
2901065 | 지상 2층 | 지상 2층 | 2900183 | 350 | 0.0975 | 0.0035 | 0.175
2901066 | 지상 2층 | 지상 2층 | 2900183 | 350 | 0.0975 | 0.0035 | 0.175
2901067 | 지상 2층 | 지상 2층 | 2900183 | 350 | 0.0975 | 0.0035 | 0.175
2901068 | 지상 2층 | 지상 2층 | 2900183 | 350 | 0.0975 | 0.0035 | 0.175
2901069 | 지상 2층 | 지상 2층 | 2900183 | 350 | 0.0975 | 0.0035 | 0.175
2901339 | 지상 2층 | 지상 2층 | 2901336 | 601.913 | 0.160478 | 0.00601913 | 0.320957
2901340 | 지상 2층 | 지상 2층 | 2901336 | 654.167 | 0.173542 | 0.00654167 | 0.347083
2901341 | 지상 2층 | 지상 2층 | 2901336 | 650 | 0.1725 | 0.0065 | 0.335
2901342 | 지상 2층 | 지상 2층 | 2901336 | 1520 | 0.39 | 0.0152 | 0.77
2901538 | 지상 2층 | 지상 2층 | 2901336 | 654.167 | 0.173542 | 0.00654167 | 0.347083
2901539 | 지상 2층 | 지상 2층 | 2901336 | 679.167 | 0.179792 | 0.00679167 | 0.359583
2901540 | 지상 2층 | 지상 2층 | 2901336 | 650 | 0.1725 | 0.0065 | 0.335
2901574 | 지상 2층 | 지상 2층 | 2901336 | 679.167 | 0.179792 | 0.00679167 | 0.359583
2901575 | 지상 2층 | 지상 2층 | 2901336 | 679.167 | 0.179792 | 0.00679167 | 0.359583
2901576 | 지상 2층 | 지상 2층 | 2901336 | 650 | 0.1725 | 0.0065 | 0.335
2901637 | 지상 2층 | 지상 2층 | 2901336 | 679.167 | 0.179792 | 0.00679167 | 0.359583
2901638 | 지상 2층 | 지상 2층 | 2901336 | 679.167 | 0.179792 | 0.00679167 | 0.359583
2901639 | 지상 2층 | 지상 2층 | 2901336 | 650 | 0.1725 | 0.0065 | 0.335
2901700 | 지상 2층 | 지상 2층 | 2901336 | 679.167 | 0.179792 | 0.00679167 | 0.359583
2901701 | 지상 2층 | 지상 2층 | 2901336 | 679.167 | 0.179792 | 0.00679167 | 0.359583
2901702 | 지상 2층 | 지상 2층 | 2901336 | 650 | 0.1725 | 0.0065 | 0.335
2901733 | 지상 2층 | 지상 2층 | 2901336 | 679.167 | 0.179792 | 0.00679167 | 0.359583
2901734 | 지상 2층 | 지상 2층 | 2901336 | 601.913 | 0.160478 | 0.00601913 | 0.320957
2901735 | 지상 2층 | 지상 2층 | 2901336 | 650 | 0.1725 | 0.0065 | 0.335
2901838 | 지상 2층 | 지상 2층 | 2901336 | 1520 | 0.39 | 0.0152 | 0.77
2901839 | 지상 2층 | 지상 2층 | 2901336 | 600 | 0.16 | 0.006 | 0.3
2901840 | 지상 2층 | 지상 2층 | 2901336 | 654.167 | 0.173542 | 0.00654167 | 0.347083
2901841 | 지상 2층 | 지상 2층 | 2901336 | 679.167 | 0.179792 | 0.00679167 | 0.359583
2901842 | 지상 2층 | 지상 2층 | 2901336 | 679.167 | 0.179792 | 0.00679167 | 0.359583
2901843 | 지상 2층 | 지상 2층 | 2901336 | 679.167 | 0.179792 | 0.00679167 | 0.359583
2901844 | 지상 2층 | 지상 2층 | 2901336 | 679.167 | 0.179792 | 0.00679167 | 0.359583
2901845 | 지상 2층 | 지상 2층 | 2901336 | 601.913 | 0.160478 | 0.00601913 | 0.320957
2901846 | 지상 2층 | 지상 2층 | 2901336 | 1520 | 0.39 | 0.0152 | 0.77
2901847 | 지상 2층 | 지상 2층 | 2901336 | 1520 | 0.39 | 0.0152 | 0.77
2901848 | 지상 2층 | 지상 2층 | 2901336 | 1520 | 0.39 | 0.0152 | 0.77
2901849 | 지상 2층 | 지상 2층 | 2901336 | 1520 | 0.39 | 0.0152 | 0.77
2901850 | 지상 2층 | 지상 2층 | 2901336 | 1520 | 0.39 | 0.0152 | 0.77
2901910 | 지상 2층 | 지상 2층 | 2901336 | 600 | 0.16 | 0.006 | 0.3
2901911 | 지상 2층 | 지상 2층 | 2901336 | 350 | 0.0975 | 0.0035 | 0.175
2901912 | 지상 2층 | 지상 2층 | 2901336 | 654.167 | 0.173542 | 0.00654167 | 0.347083
2901913 | 지상 2층 | 지상 2층 | 2901336 | 679.167 | 0.179792 | 0.00679167 | 0.359583
2901914 | 지상 2층 | 지상 2층 | 2901336 | 679.167 | 0.179792 | 0.00679167 | 0.359583
2901915 | 지상 2층 | 지상 2층 | 2901336 | 679.167 | 0.179792 | 0.00679167 | 0.359583
2901916 | 지상 2층 | 지상 2층 | 2901336 | 679.167 | 0.179792 | 0.00679167 | 0.359583
2901917 | 지상 2층 | 지상 2층 | 2901336 | 601.913 | 0.160478 | 0.00601913 | 0.320957
2901918 | 지상 2층 | 지상 2층 | 2901336 | 600 | 0.16 | 0.006 | 0.3
2901919 | 지상 2층 | 지상 2층 | 2901336 | 600 | 0.16 | 0.006 | 0.3
2901920 | 지상 2층 | 지상 2층 | 2901336 | 600 | 0.16 | 0.006 | 0.3
2901921 | 지상 2층 | 지상 2층 | 2901336 | 600 | 0.16 | 0.006 | 0.3
2901922 | 지상 2층 | 지상 2층 | 2901336 | 600 | 0.16 | 0.006 | 0.3
2901979 | 지상 2층 | 지상 2층 | 2901336 | 350 | 0.0975 | 0.0035 | 0.175
2901980 | 지상 2층 | 지상 2층 | 2901336 | 650 | 0.1725 | 0.0065 | 0.335
2901981 | 지상 2층 | 지상 2층 | 2901336 | 654.167 | 0.173542 | 0.00654167 | 0.347083
2901982 | 지상 2층 | 지상 2층 | 2901336 | 679.167 | 0.179792 | 0.00679167 | 0.359583
2901983 | 지상 2층 | 지상 2층 | 2901336 | 679.167 | 0.179792 | 0.00679167 | 0.359583
2901984 | 지상 2층 | 지상 2층 | 2901336 | 679.167 | 0.179792 | 0.00679167 | 0.359583
2901985 | 지상 2층 | 지상 2층 | 2901336 | 679.167 | 0.179792 | 0.00679167 | 0.359583
2901986 | 지상 2층 | 지상 2층 | 2901336 | 601.913 | 0.160478 | 0.00601913 | 0.320957
2901987 | 지상 2층 | 지상 2층 | 2901336 | 350 | 0.0975 | 0.0035 | 0.175
2901988 | 지상 2층 | 지상 2층 | 2901336 | 350 | 0.0975 | 0.0035 | 0.175
2901989 | 지상 2층 | 지상 2층 | 2901336 | 350 | 0.0975 | 0.0035 | 0.175
2901990 | 지상 2층 | 지상 2층 | 2901336 | 350 | 0.0975 | 0.0035 | 0.175
2901991 | 지상 2층 | 지상 2층 | 2901336 | 350 | 0.0975 | 0.0035 | 0.175
2902264 | 지상 2층 | 지상 2층 | 2902261 | 995 | 0.25875 | 0.00995 | 0.5175
2902265 | 지상 2층 | 지상 2층 | 2902261 | 1077.03 | 0.279257 | 0.0107703 | 0.558513
2902266 | 지상 2층 | 지상 2층 | 2902261 | 650 | 0.1725 | 0.0065 | 0.335
2902267 | 지상 2층 | 지상 2층 | 2902261 | 1520 | 0.39 | 0.0152 | 0.77
2902547 | 지상 2층 | 지상 2층 | 2902261 | 1077.03 | 0.279257 | 0.0107703 | 0.558513
2902548 | 지상 2층 | 지상 2층 | 2902261 | 1020 | 0.265 | 0.0102 | 0.53
2902549 | 지상 2층 | 지상 2층 | 2902261 | 650 | 0.1725 | 0.0065 | 0.335
2902804 | 지상 2층 | 지상 2층 | 2902261 | 1020 | 0.265 | 0.0102 | 0.53
2902805 | 지상 2층 | 지상 2층 | 2902261 | 1020 | 0.265 | 0.0102 | 0.53
2902806 | 지상 2층 | 지상 2층 | 2902261 | 650 | 0.1725 | 0.0065 | 0.335
2902859 | 지상 2층 | 지상 2층 | 2902261 | 1020 | 0.265 | 0.0102 | 0.53
2902860 | 지상 2층 | 지상 2층 | 2902261 | 1020 | 0.265 | 0.0102 | 0.53
2902861 | 지상 2층 | 지상 2층 | 2902261 | 650 | 0.1725 | 0.0065 | 0.335
2902950 | 지상 2층 | 지상 2층 | 2902261 | 1020 | 0.265 | 0.0102 | 0.53
2902951 | 지상 2층 | 지상 2층 | 2902261 | 995 | 0.25875 | 0.00995 | 0.5175
2902952 | 지상 2층 | 지상 2층 | 2902261 | 650 | 0.1725 | 0.0065 | 0.335
2903145 | 지상 2층 | 지상 2층 | 2902261 | 1520 | 0.39 | 0.0152 | 0.77
2903146 | 지상 2층 | 지상 2층 | 2902261 | 600 | 0.16 | 0.006 | 0.3
2903147 | 지상 2층 | 지상 2층 | 2902261 | 1077.03 | 0.279257 | 0.0107703 | 0.558513
2903148 | 지상 2층 | 지상 2층 | 2902261 | 1020 | 0.265 | 0.0102 | 0.53
2903149 | 지상 2층 | 지상 2층 | 2902261 | 1020 | 0.265 | 0.0102 | 0.53
2903150 | 지상 2층 | 지상 2층 | 2902261 | 1020 | 0.265 | 0.0102 | 0.53
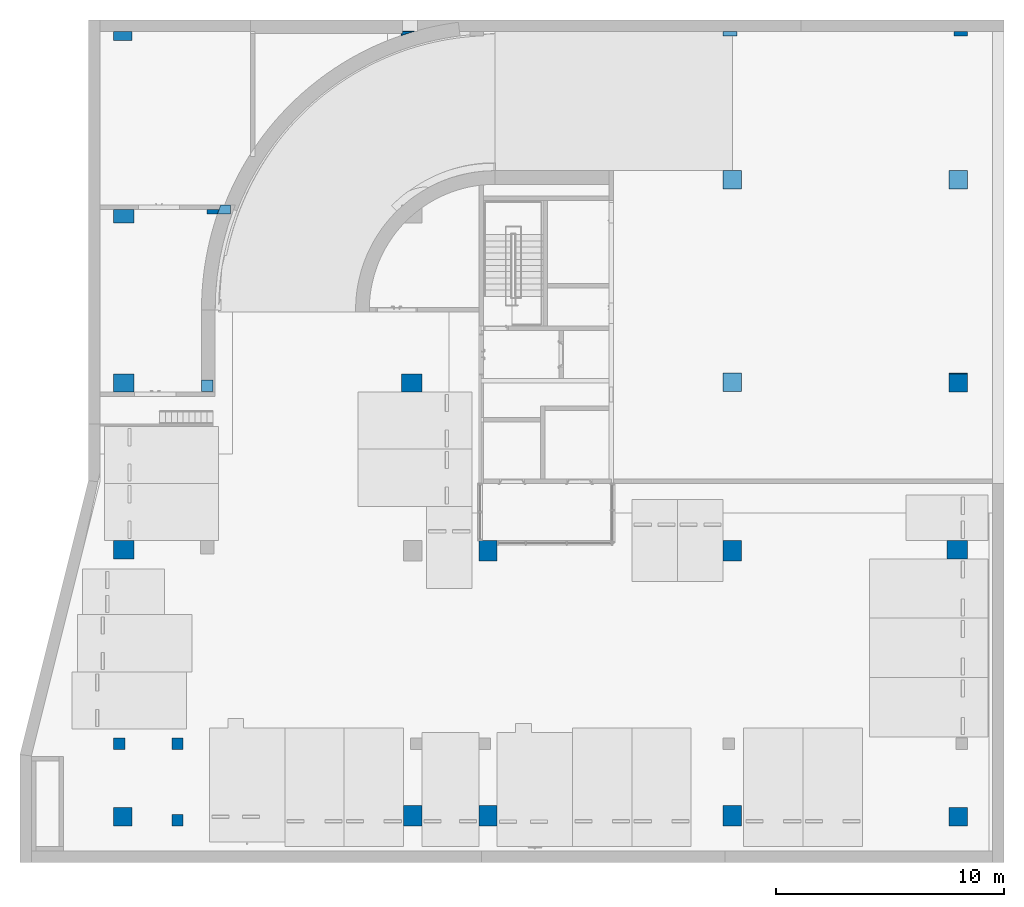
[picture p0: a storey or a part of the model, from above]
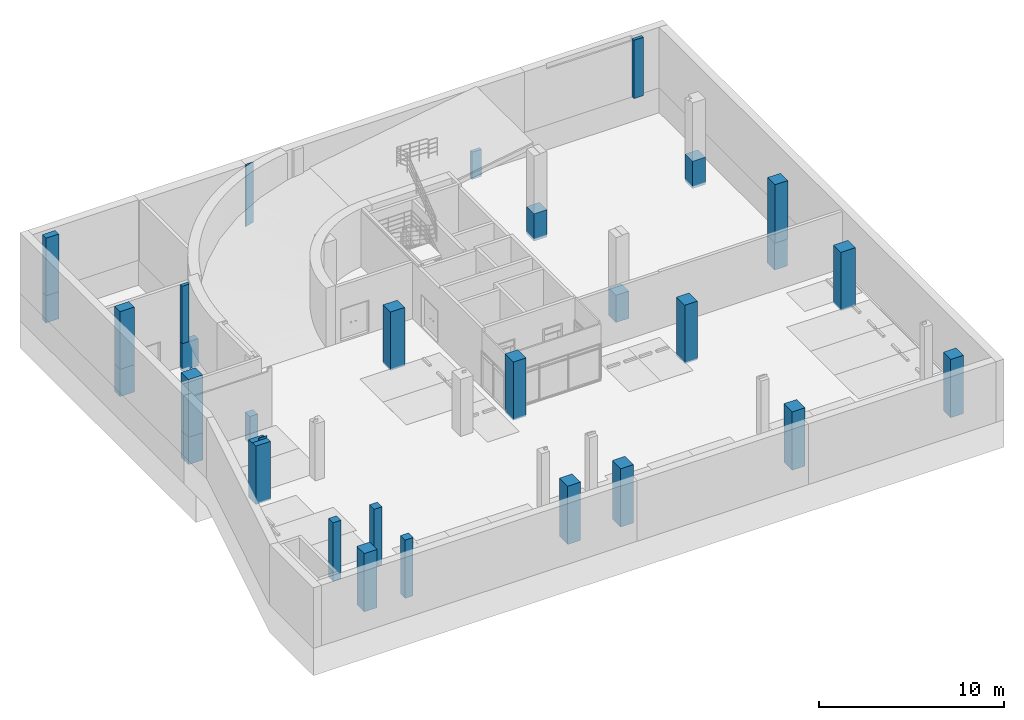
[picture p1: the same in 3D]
Properties of the parts of a building model (IFC2X3), part 15 of 39

# IfcMember: 직사각형 멀리언:CW200-직사각형 멀리언 50x200mm (8700)
Name (직사각형 멀리언:CW200-직사각형 멀리언 50x200mm:...) | In | 레벨 | 호스트 ID | 길이 (mm) = Span (mm) | 면적 (m2) = CrossSectionArea (m2) | 체적 (m3) = NetVolume (m3) | NetSurfaceArea (m2)
2903151 | 지상 2층 | 지상 2층 | 2902261 | 995 | 0.25875 | 0.00995 | 0.5175
2903152 | 지상 2층 | 지상 2층 | 2902261 | 1520 | 0.39 | 0.0152 | 0.77
2903153 | 지상 2층 | 지상 2층 | 2902261 | 1520 | 0.39 | 0.0152 | 0.77
2903154 | 지상 2층 | 지상 2층 | 2902261 | 1520 | 0.39 | 0.0152 | 0.77
2903155 | 지상 2층 | 지상 2층 | 2902261 | 1520 | 0.39 | 0.0152 | 0.77
2903234 | 지상 2층 | 지상 2층 | 2902261 | 600 | 0.16 | 0.006 | 0.3
2903235 | 지상 2층 | 지상 2층 | 2902261 | 350 | 0.0975 | 0.0035 | 0.175
2903236 | 지상 2층 | 지상 2층 | 2902261 | 1077.03 | 0.279257 | 0.0107703 | 0.558513
2903237 | 지상 2층 | 지상 2층 | 2902261 | 1020 | 0.265 | 0.0102 | 0.53
2903238 | 지상 2층 | 지상 2층 | 2902261 | 1020 | 0.265 | 0.0102 | 0.53
2903239 | 지상 2층 | 지상 2층 | 2902261 | 1020 | 0.265 | 0.0102 | 0.53
2903240 | 지상 2층 | 지상 2층 | 2902261 | 995 | 0.25875 | 0.00995 | 0.5175
2903241 | 지상 2층 | 지상 2층 | 2902261 | 600 | 0.16 | 0.006 | 0.3
2903242 | 지상 2층 | 지상 2층 | 2902261 | 600 | 0.16 | 0.006 | 0.3
2903243 | 지상 2층 | 지상 2층 | 2902261 | 600 | 0.16 | 0.006 | 0.3
2903244 | 지상 2층 | 지상 2층 | 2902261 | 600 | 0.16 | 0.006 | 0.3
2903310 | 지상 2층 | 지상 2층 | 2902261 | 350 | 0.0975 | 0.0035 | 0.175
2903311 | 지상 2층 | 지상 2층 | 2902261 | 650 | 0.1725 | 0.0065 | 0.335
2903312 | 지상 2층 | 지상 2층 | 2902261 | 1077.03 | 0.279257 | 0.0107703 | 0.558513
2903313 | 지상 2층 | 지상 2층 | 2902261 | 1020 | 0.265 | 0.0102 | 0.53
2903314 | 지상 2층 | 지상 2층 | 2902261 | 1020 | 0.265 | 0.0102 | 0.53
2903315 | 지상 2층 | 지상 2층 | 2902261 | 1020 | 0.265 | 0.0102 | 0.53
2903316 | 지상 2층 | 지상 2층 | 2902261 | 995 | 0.25875 | 0.00995 | 0.5175
2903317 | 지상 2층 | 지상 2층 | 2902261 | 350 | 0.0975 | 0.0035 | 0.175
2903318 | 지상 2층 | 지상 2층 | 2902261 | 350 | 0.0975 | 0.0035 | 0.175
2903319 | 지상 2층 | 지상 2층 | 2902261 | 350 | 0.0975 | 0.0035 | 0.175
2903320 | 지상 2층 | 지상 2층 | 2902261 | 350 | 0.0975 | 0.0035 | 0.175
2903633 | 지상 2층 | 지상 2층 | 2903630 | 1095.11 | 0.283779 | 0.0109511 | 0.567557
2903634 | 지상 2층 | 지상 2층 | 2903630 | 995 | 0.25875 | 0.00995 | 0.5175
2903635 | 지상 2층 | 지상 2층 | 2903630 | 650 | 0.1725 | 0.0065 | 0.335
2903636 | 지상 2층 | 지상 2층 | 2903630 | 1520 | 0.39 | 0.0152 | 0.77
2903932 | 지상 2층 | 지상 2층 | 2903630 | 995 | 0.25875 | 0.00995 | 0.5175
2903933 | 지상 2층 | 지상 2층 | 2903630 | 1020 | 0.265 | 0.0102 | 0.53
2903934 | 지상 2층 | 지상 2층 | 2903630 | 650 | 0.1725 | 0.0065 | 0.335
2904014 | 지상 2층 | 지상 2층 | 2903630 | 1020 | 0.265 | 0.0102 | 0.53
2904015 | 지상 2층 | 지상 2층 | 2903630 | 1020 | 0.265 | 0.0102 | 0.53
2904016 | 지상 2층 | 지상 2층 | 2903630 | 650 | 0.1725 | 0.0065 | 0.335
2904075 | 지상 2층 | 지상 2층 | 2903630 | 1020 | 0.265 | 0.0102 | 0.53
2904076 | 지상 2층 | 지상 2층 | 2903630 | 1020 | 0.265 | 0.0102 | 0.53
2904077 | 지상 2층 | 지상 2층 | 2903630 | 650 | 0.1725 | 0.0065 | 0.335
2904229 | 지상 2층 | 지상 2층 | 2903630 | 1020 | 0.265 | 0.0102 | 0.53
2904230 | 지상 2층 | 지상 2층 | 2903630 | 1095.11 | 0.283779 | 0.0109511 | 0.567557
2904231 | 지상 2층 | 지상 2층 | 2903630 | 650 | 0.1725 | 0.0065 | 0.335
2904454 | 지상 2층 | 지상 2층 | 2903630 | 1520 | 0.39 | 0.0152 | 0.77
2904455 | 지상 2층 | 지상 2층 | 2903630 | 600 | 0.16 | 0.006 | 0.3
2904456 | 지상 2층 | 지상 2층 | 2903630 | 995 | 0.25875 | 0.00995 | 0.5175
2904457 | 지상 2층 | 지상 2층 | 2903630 | 1020 | 0.265 | 0.0102 | 0.53
2904458 | 지상 2층 | 지상 2층 | 2903630 | 1020 | 0.265 | 0.0102 | 0.53
2904459 | 지상 2층 | 지상 2층 | 2903630 | 1020 | 0.265 | 0.0102 | 0.53
2904460 | 지상 2층 | 지상 2층 | 2903630 | 1095.11 | 0.283779 | 0.0109511 | 0.567557
2904461 | 지상 2층 | 지상 2층 | 2903630 | 1520 | 0.39 | 0.0152 | 0.77
2904462 | 지상 2층 | 지상 2층 | 2903630 | 1520 | 0.39 | 0.0152 | 0.77
2904463 | 지상 2층 | 지상 2층 | 2903630 | 1520 | 0.39 | 0.0152 | 0.77
2904464 | 지상 2층 | 지상 2층 | 2903630 | 1520 | 0.39 | 0.0152 | 0.77
2904583 | 지상 2층 | 지상 2층 | 2903630 | 600 | 0.16 | 0.006 | 0.3
2904584 | 지상 2층 | 지상 2층 | 2903630 | 350 | 0.0975 | 0.0035 | 0.175
2904585 | 지상 2층 | 지상 2층 | 2903630 | 995 | 0.25875 | 0.00995 | 0.5175
2904586 | 지상 2층 | 지상 2층 | 2903630 | 1020 | 0.265 | 0.0102 | 0.53
2904587 | 지상 2층 | 지상 2층 | 2903630 | 1020 | 0.265 | 0.0102 | 0.53
2904588 | 지상 2층 | 지상 2층 | 2903630 | 1020 | 0.265 | 0.0102 | 0.53
2904589 | 지상 2층 | 지상 2층 | 2903630 | 1095.11 | 0.283779 | 0.0109511 | 0.567557
2904591 | 지상 2층 | 지상 2층 | 2903630 | 600 | 0.16 | 0.006 | 0.3
2904592 | 지상 2층 | 지상 2층 | 2903630 | 600 | 0.16 | 0.006 | 0.3
2904593 | 지상 2층 | 지상 2층 | 2903630 | 600 | 0.16 | 0.006 | 0.3
2904594 | 지상 2층 | 지상 2층 | 2903630 | 600 | 0.16 | 0.006 | 0.3
2904658 | 지상 2층 | 지상 2층 | 2903630 | 350 | 0.0975 | 0.0035 | 0.175
2904659 | 지상 2층 | 지상 2층 | 2903630 | 650 | 0.1725 | 0.0065 | 0.335
2904660 | 지상 2층 | 지상 2층 | 2903630 | 995 | 0.25875 | 0.00995 | 0.5175
2904661 | 지상 2층 | 지상 2층 | 2903630 | 1020 | 0.265 | 0.0102 | 0.53
2904662 | 지상 2층 | 지상 2층 | 2903630 | 1020 | 0.265 | 0.0102 | 0.53
2904663 | 지상 2층 | 지상 2층 | 2903630 | 1020 | 0.265 | 0.0102 | 0.53
2904664 | 지상 2층 | 지상 2층 | 2903630 | 1095.11 | 0.283779 | 0.0109511 | 0.567557
2904666 | 지상 2층 | 지상 2층 | 2903630 | 350 | 0.0975 | 0.0035 | 0.175
2904667 | 지상 2층 | 지상 2층 | 2903630 | 350 | 0.0975 | 0.0035 | 0.175
2904668 | 지상 2층 | 지상 2층 | 2903630 | 350 | 0.0975 | 0.0035 | 0.175
2904669 | 지상 2층 | 지상 2층 | 2903630 | 350 | 0.0975 | 0.0035 | 0.175
2904977 | 지상 2층 | 지상 2층 | 2904974 | 1175 | 0.30375 | 0.01175 | 0.6075
2904978 | 지상 2층 | 지상 2층 | 2904974 | 1175 | 0.30375 | 0.01175 | 0.6075
2904979 | 지상 2층 | 지상 2층 | 2904974 | 650 | 0.1725 | 0.0065 | 0.335
2904980 | 지상 2층 | 지상 2층 | 2904974 | 1520 | 0.39 | 0.0152 | 0.77
2906913 | 지상 2층 | 지상 2층 | 2904974 | 1175 | 0.30375 | 0.01175 | 0.6075
2906914 | 지상 2층 | 지상 2층 | 2904974 | 1175 | 0.30375 | 0.01175 | 0.6075
2906915 | 지상 2층 | 지상 2층 | 2904974 | 650 | 0.1725 | 0.0065 | 0.335
2907008 | 지상 2층 | 지상 2층 | 2904974 | 1520 | 0.39 | 0.0152 | 0.77
2907009 | 지상 2층 | 지상 2층 | 2904974 | 600 | 0.16 | 0.006 | 0.3
2907010 | 지상 2층 | 지상 2층 | 2904974 | 1175 | 0.30375 | 0.01175 | 0.6075
2907011 | 지상 2층 | 지상 2층 | 2904974 | 1175 | 0.30375 | 0.01175 | 0.6075
2907012 | 지상 2층 | 지상 2층 | 2904974 | 1520 | 0.39 | 0.0152 | 0.77
2907091 | 지상 2층 | 지상 2층 | 2904974 | 600 | 0.16 | 0.006 | 0.3
2907092 | 지상 2층 | 지상 2층 | 2904974 | 350 | 0.0975 | 0.0035 | 0.175
2907093 | 지상 2층 | 지상 2층 | 2904974 | 1175 | 0.30375 | 0.01175 | 0.6075
2907094 | 지상 2층 | 지상 2층 | 2904974 | 1175 | 0.30375 | 0.01175 | 0.6075
2907095 | 지상 2층 | 지상 2층 | 2904974 | 600 | 0.16 | 0.006 | 0.3
2907164 | 지상 2층 | 지상 2층 | 2904974 | 350 | 0.0975 | 0.0035 | 0.175
2907165 | 지상 2층 | 지상 2층 | 2904974 | 650 | 0.1725 | 0.0065 | 0.335
2907166 | 지상 2층 | 지상 2층 | 2904974 | 1175 | 0.30375 | 0.01175 | 0.6075
2907167 | 지상 2층 | 지상 2층 | 2904974 | 1175 | 0.30375 | 0.01175 | 0.6075
2907168 | 지상 2층 | 지상 2층 | 2904974 | 350 | 0.0975 | 0.0035 | 0.175
2905068 | 지상 2층 | 지상 2층 | 2905064 | 1018.75 | 0.264687 | 0.0101875 | 0.529375
2905069 | 지상 2층 | 지상 2층 | 2905064 | 1101.02 | 0.285254 | 0.0110102 | 0.570508
2905070 | 지상 2층 | 지상 2층 | 2905064 | 650 | 0.1725 | 0.0065 | 0.335
2905071 | 지상 2층 | 지상 2층 | 2905064 | 1520 | 0.39 | 0.0152 | 0.77
2907347 | 지상 2층 | 지상 2층 | 2905064 | 1101.02 | 0.285254 | 0.0110102 | 0.570508
2907348 | 지상 2층 | 지상 2층 | 2905064 | 1043.75 | 0.270937 | 0.0104375 | 0.541875
2907349 | 지상 2층 | 지상 2층 | 2905064 | 650 | 0.1725 | 0.0065 | 0.335
2907433 | 지상 2층 | 지상 2층 | 2905064 | 1043.75 | 0.270938 | 0.0104375 | 0.541875
2907434 | 지상 2층 | 지상 2층 | 2905064 | 1043.75 | 0.270937 | 0.0104375 | 0.541875
2907435 | 지상 2층 | 지상 2층 | 2905064 | 650 | 0.1725 | 0.0065 | 0.335
2907522 | 지상 2층 | 지상 2층 | 2905064 | 1520 | 0.39 | 0.0152 | 0.77
2907523 | 지상 2층 | 지상 2층 | 2905064 | 600 | 0.16 | 0.006 | 0.3
2907524 | 지상 2층 | 지상 2층 | 2905064 | 1101.02 | 0.285254 | 0.0110102 | 0.570508
2907525 | 지상 2층 | 지상 2층 | 2905064 | 1043.75 | 0.270938 | 0.0104375 | 0.541875
2907526 | 지상 2층 | 지상 2층 | 2905064 | 1043.75 | 0.270938 | 0.0104375 | 0.541875
2907527 | 지상 2층 | 지상 2층 | 2905064 | 1520 | 0.39 | 0.0152 | 0.77
2907528 | 지상 2층 | 지상 2층 | 2905064 | 1520 | 0.39 | 0.0152 | 0.77
2907658 | 지상 2층 | 지상 2층 | 2905064 | 1043.75 | 0.270938 | 0.0104375 | 0.541875
2907659 | 지상 2층 | 지상 2층 | 2905064 | 1018.75 | 0.264687 | 0.0101875 | 0.529375
2907660 | 지상 2층 | 지상 2층 | 2905064 | 1018.75 | 0.264687 | 0.0101875 | 0.529375
2907661 | 지상 2층 | 지상 2층 | 2905064 | 650 | 0.1725 | 0.0065 | 0.335
2907662 | 지상 2층 | 지상 2층 | 2905064 | 1520 | 0.39 | 0.0152 | 0.77
2907846 | 지상 2층 | 지상 2층 | 2905064 | 600 | 0.16 | 0.006 | 0.3
2907847 | 지상 2층 | 지상 2층 | 2905064 | 350 | 0.0975 | 0.0035 | 0.175
2907848 | 지상 2층 | 지상 2층 | 2905064 | 1101.02 | 0.285254 | 0.0110102 | 0.570508
2907849 | 지상 2층 | 지상 2층 | 2905064 | 1043.75 | 0.270938 | 0.0104375 | 0.541875
2907850 | 지상 2층 | 지상 2층 | 2905064 | 1043.75 | 0.270938 | 0.0104375 | 0.541875
2907851 | 지상 2층 | 지상 2층 | 2905064 | 1018.75 | 0.264687 | 0.0101875 | 0.529375
2907853 | 지상 2층 | 지상 2층 | 2905064 | 600 | 0.16 | 0.006 | 0.3
2907854 | 지상 2층 | 지상 2층 | 2905064 | 600 | 0.16 | 0.006 | 0.3
2907855 | 지상 2층 | 지상 2층 | 2905064 | 600 | 0.16 | 0.006 | 0.3
2907926 | 지상 2층 | 지상 2층 | 2905064 | 350 | 0.0975 | 0.0035 | 0.175
2907927 | 지상 2층 | 지상 2층 | 2905064 | 650 | 0.1725 | 0.0065 | 0.335
2907928 | 지상 2층 | 지상 2층 | 2905064 | 1101.02 | 0.285254 | 0.0110102 | 0.570508
2907929 | 지상 2층 | 지상 2층 | 2905064 | 1043.75 | 0.270938 | 0.0104375 | 0.541875
2907930 | 지상 2층 | 지상 2층 | 2905064 | 1043.75 | 0.270938 | 0.0104375 | 0.541875
2907931 | 지상 2층 | 지상 2층 | 2905064 | 1018.75 | 0.264687 | 0.0101875 | 0.529375
2907933 | 지상 2층 | 지상 2층 | 2905064 | 350 | 0.0975 | 0.0035 | 0.175
2907934 | 지상 2층 | 지상 2층 | 2905064 | 350 | 0.0975 | 0.0035 | 0.175
2907935 | 지상 2층 | 지상 2층 | 2905064 | 350 | 0.0975 | 0.0035 | 0.175
2905220 | 지상 2층 | 지상 2층 | 2905217 | 1093.57 | 0.283394 | 0.0109357 | 0.566787
2905221 | 지상 2층 | 지상 2층 | 2905217 | 1018.75 | 0.264687 | 0.0101875 | 0.529375
2905222 | 지상 2층 | 지상 2층 | 2905217 | 650 | 0.1725 | 0.0065 | 0.335
2905223 | 지상 2층 | 지상 2층 | 2905217 | 1520 | 0.39 | 0.0152 | 0.77
2908355 | 지상 2층 | 지상 2층 | 2905217 | 1520 | 0.39 | 0.0152 | 0.77
2908356 | 지상 2층 | 지상 2층 | 2905217 | 600 | 0.16 | 0.006 | 0.3
2908357 | 지상 2층 | 지상 2층 | 2905217 | 1018.75 | 0.264687 | 0.0101875 | 0.529375
2908443 | 지상 2층 | 지상 2층 | 2905217 | 1018.75 | 0.264687 | 0.0101875 | 0.529375
2908444 | 지상 2층 | 지상 2층 | 2905217 | 1043.75 | 0.270937 | 0.0104375 | 0.541875
2908445 | 지상 2층 | 지상 2층 | 2905217 | 1043.75 | 0.270938 | 0.0104375 | 0.541875
2908446 | 지상 2층 | 지상 2층 | 2905217 | 650 | 0.1725 | 0.0065 | 0.335
2908447 | 지상 2층 | 지상 2층 | 2905217 | 1520 | 0.39 | 0.0152 | 0.77
2908508 | 지상 2층 | 지상 2층 | 2905217 | 600 | 0.16 | 0.006 | 0.3
2908509 | 지상 2층 | 지상 2층 | 2905217 | 350 | 0.0975 | 0.0035 | 0.175
2908510 | 지상 2층 | 지상 2층 | 2905217 | 1018.75 | 0.264687 | 0.0101875 | 0.529375
2908511 | 지상 2층 | 지상 2층 | 2905217 | 1043.75 | 0.270938 | 0.0104375 | 0.541875
2908512 | 지상 2층 | 지상 2층 | 2905217 | 600 | 0.16 | 0.006 | 0.3
2908583 | 지상 2층 | 지상 2층 | 2905217 | 350 | 0.0975 | 0.0035 | 0.175
2908584 | 지상 2층 | 지상 2층 | 2905217 | 650 | 0.1725 | 0.0065 | 0.335
2908585 | 지상 2층 | 지상 2층 | 2905217 | 1018.75 | 0.264687 | 0.0101875 | 0.529375
2908586 | 지상 2층 | 지상 2층 | 2905217 | 1043.75 | 0.270938 | 0.0104375 | 0.541875
2908587 | 지상 2층 | 지상 2층 | 2905217 | 350 | 0.0975 | 0.0035 | 0.175
2908707 | 지상 2층 | 지상 2층 | 2905217 | 1043.75 | 0.270938 | 0.0104375 | 0.541875
2908708 | 지상 2층 | 지상 2층 | 2905217 | 1043.75 | 0.270937 | 0.0104375 | 0.541875
2908709 | 지상 2층 | 지상 2층 | 2905217 | 1043.75 | 0.270938 | 0.0104375 | 0.541875
2908710 | 지상 2층 | 지상 2층 | 2905217 | 1043.75 | 0.270938 | 0.0104375 | 0.541875
2908711 | 지상 2층 | 지상 2층 | 2905217 | 1043.75 | 0.270938 | 0.0104375 | 0.541875
2908712 | 지상 2층 | 지상 2층 | 2905217 | 650 | 0.1725 | 0.0065 | 0.335
2908713 | 지상 2층 | 지상 2층 | 2905217 | 350 | 0.0975 | 0.0035 | 0.175
2908714 | 지상 2층 | 지상 2층 | 2905217 | 600 | 0.16 | 0.006 | 0.3
2908715 | 지상 2층 | 지상 2층 | 2905217 | 1520 | 0.39 | 0.0152 | 0.77
2908779 | 지상 2층 | 지상 2층 | 2905217 | 1043.75 | 0.270938 | 0.0104375 | 0.541875
2908780 | 지상 2층 | 지상 2층 | 2905217 | 1093.57 | 0.283394 | 0.0109357 | 0.566787
2908781 | 지상 2층 | 지상 2층 | 2905217 | 1093.57 | 0.283394 | 0.0109357 | 0.566787
2908782 | 지상 2층 | 지상 2층 | 2905217 | 1093.57 | 0.283394 | 0.0109357 | 0.566787
2908783 | 지상 2층 | 지상 2층 | 2905217 | 1093.57 | 0.283394 | 0.0109357 | 0.566787
2908784 | 지상 2층 | 지상 2층 | 2905217 | 650 | 0.1725 | 0.0065 | 0.335
2908785 | 지상 2층 | 지상 2층 | 2905217 | 350 | 0.0975 | 0.0035 | 0.175
2908786 | 지상 2층 | 지상 2층 | 2905217 | 600 | 0.16 | 0.006 | 0.3
2908787 | 지상 2층 | 지상 2층 | 2905217 | 1520 | 0.39 | 0.0152 | 0.77
2905355 | 지상 2층 | 지상 2층 | 2905351 | 912.5 | 0.238125 | 0.009125 | 0.47625
2905356 | 지상 2층 | 지상 2층 | 2905351 | 988.599 | 0.25715 | 0.00988599 | 0.514299
2905357 | 지상 2층 | 지상 2층 | 2905351 | 650 | 0.1725 | 0.0065 | 0.335
2905358 | 지상 2층 | 지상 2층 | 2905351 | 1520 | 0.39 | 0.0152 | 0.77
2909236 | 지상 2층 | 지상 2층 | 2905351 | 1520 | 0.39 | 0.0152 | 0.77
2909237 | 지상 2층 | 지상 2층 | 2905351 | 600 | 0.16 | 0.006 | 0.3
2909238 | 지상 2층 | 지상 2층 | 2905351 | 988.599 | 0.25715 | 0.00988599 | 0.514299
2909322 | 지상 2층 | 지상 2층 | 2905351 | 988.599 | 0.25715 | 0.00988599 | 0.514299
2909323 | 지상 2층 | 지상 2층 | 2905351 | 937.5 | 0.244375 | 0.009375 | 0.48875
2909324 | 지상 2층 | 지상 2층 | 2905351 | 937.5 | 0.244375 | 0.009375 | 0.48875
2909325 | 지상 2층 | 지상 2층 | 2905351 | 650 | 0.1725 | 0.0065 | 0.335
2909326 | 지상 2층 | 지상 2층 | 2905351 | 1520 | 0.39 | 0.0152 | 0.77
2909482 | 지상 2층 | 지상 2층 | 2905351 | 600 | 0.16 | 0.006 | 0.3
2909483 | 지상 2층 | 지상 2층 | 2905351 | 350 | 0.0975 | 0.0035 | 0.175
2909484 | 지상 2층 | 지상 2층 | 2905351 | 988.599 | 0.25715 | 0.00988599 | 0.514299
2909485 | 지상 2층 | 지상 2층 | 2905351 | 937.5 | 0.244375 | 0.009375 | 0.48875
2909486 | 지상 2층 | 지상 2층 | 2905351 | 600 | 0.16 | 0.006 | 0.3
2909567 | 지상 2층 | 지상 2층 | 2905351 | 937.5 | 0.244375 | 0.009375 | 0.48875
2909568 | 지상 2층 | 지상 2층 | 2905351 | 937.5 | 0.244375 | 0.009375 | 0.48875
2909569 | 지상 2층 | 지상 2층 | 2905351 | 937.5 | 0.244375 | 0.009375 | 0.48875
2909570 | 지상 2층 | 지상 2층 | 2905351 | 937.5 | 0.244375 | 0.009375 | 0.48875
2909571 | 지상 2층 | 지상 2층 | 2905351 | 650 | 0.1725 | 0.0065 | 0.335
2909572 | 지상 2층 | 지상 2층 | 2905351 | 600 | 0.16 | 0.006 | 0.3
2909573 | 지상 2층 | 지상 2층 | 2905351 | 1520 | 0.39 | 0.0152 | 0.77
2909667 | 지상 2층 | 지상 2층 | 2905351 | 937.5 | 0.244375 | 0.009375 | 0.48875
2909668 | 지상 2층 | 지상 2층 | 2905351 | 912.5 | 0.238125 | 0.009125 | 0.47625
2909669 | 지상 2층 | 지상 2층 | 2905351 | 912.5 | 0.238125 | 0.009125 | 0.47625
2909670 | 지상 2층 | 지상 2층 | 2905351 | 912.5 | 0.238125 | 0.009125 | 0.47625
2909671 | 지상 2층 | 지상 2층 | 2905351 | 650 | 0.1725 | 0.0065 | 0.335
2909672 | 지상 2층 | 지상 2층 | 2905351 | 600 | 0.16 | 0.006 | 0.3
2909673 | 지상 2층 | 지상 2층 | 2905351 | 1520 | 0.39 | 0.0152 | 0.77
2909736 | 지상 2층 | 지상 2층 | 2905351 | 350 | 0.0975 | 0.0035 | 0.175
2909737 | 지상 2층 | 지상 2층 | 2905351 | 650 | 0.1725 | 0.0065 | 0.335
2909738 | 지상 2층 | 지상 2층 | 2905351 | 988.599 | 0.25715 | 0.00988599 | 0.514299
2909739 | 지상 2층 | 지상 2층 | 2905351 | 937.5 | 0.244375 | 0.009375 | 0.48875
2909740 | 지상 2층 | 지상 2층 | 2905351 | 937.5 | 0.244375 | 0.009375 | 0.48875
2909741 | 지상 2층 | 지상 2층 | 2905351 | 912.5 | 0.238125 | 0.009125 | 0.47625
2909742 | 지상 2층 | 지상 2층 | 2905351 | 350 | 0.0975 | 0.0035 | 0.175
2909743 | 지상 2층 | 지상 2층 | 2905351 | 350 | 0.0975 | 0.0035 | 0.175
2909744 | 지상 2층 | 지상 2층 | 2905351 | 350 | 0.0975 | 0.0035 | 0.175
2905466 | 지상 2층 | 지상 2층 | 2905462 | 1001.66 | 0.260415 | 0.0100166 | 0.520829
2905467 | 지상 2층 | 지상 2층 | 2905462 | 912.5 | 0.238125 | 0.009125 | 0.47625
2905468 | 지상 2층 | 지상 2층 | 2905462 | 650 | 0.1725 | 0.0065 | 0.335
2905469 | 지상 2층 | 지상 2층 | 2905462 | 1520 | 0.39 | 0.0152 | 0.77
2909966 | 지상 2층 | 지상 2층 | 2905462 | 1520 | 0.39 | 0.0152 | 0.77
2909967 | 지상 2층 | 지상 2층 | 2905462 | 600 | 0.16 | 0.006 | 0.3
2909968 | 지상 2층 | 지상 2층 | 2905462 | 912.5 | 0.238125 | 0.009125 | 0.47625
2910024 | 지상 2층 | 지상 2층 | 2905462 | 912.5 | 0.238125 | 0.009125 | 0.47625
2910025 | 지상 2층 | 지상 2층 | 2905462 | 937.5 | 0.244375 | 0.009375 | 0.48875
2910026 | 지상 2층 | 지상 2층 | 2905462 | 937.5 | 0.244375 | 0.009375 | 0.48875
2910027 | 지상 2층 | 지상 2층 | 2905462 | 650 | 0.1725 | 0.0065 | 0.335
2910028 | 지상 2층 | 지상 2층 | 2905462 | 1520 | 0.39 | 0.0152 | 0.77
2910088 | 지상 2층 | 지상 2층 | 2905462 | 600 | 0.16 | 0.006 | 0.3
2910089 | 지상 2층 | 지상 2층 | 2905462 | 350 | 0.0975 | 0.0035 | 0.175
2910090 | 지상 2층 | 지상 2층 | 2905462 | 912.5 | 0.238125 | 0.009125 | 0.47625
2910091 | 지상 2층 | 지상 2층 | 2905462 | 937.5 | 0.244375 | 0.009375 | 0.48875
2910092 | 지상 2층 | 지상 2층 | 2905462 | 600 | 0.16 | 0.006 | 0.3
2910186 | 지상 2층 | 지상 2층 | 2905462 | 937.5 | 0.244375 | 0.009375 | 0.48875
2910187 | 지상 2층 | 지상 2층 | 2905462 | 937.5 | 0.244375 | 0.009375 | 0.48875
2910188 | 지상 2층 | 지상 2층 | 2905462 | 937.5 | 0.244375 | 0.009375 | 0.48875
2910189 | 지상 2층 | 지상 2층 | 2905462 | 937.5 | 0.244375 | 0.009375 | 0.48875
2910190 | 지상 2층 | 지상 2층 | 2905462 | 650 | 0.1725 | 0.0065 | 0.335
2910191 | 지상 2층 | 지상 2층 | 2905462 | 600 | 0.16 | 0.006 | 0.3
2910192 | 지상 2층 | 지상 2층 | 2905462 | 1520 | 0.39 | 0.0152 | 0.77
2910272 | 지상 2층 | 지상 2층 | 2905462 | 937.5 | 0.244375 | 0.009375 | 0.48875
2910273 | 지상 2층 | 지상 2층 | 2905462 | 1001.66 | 0.260415 | 0.0100166 | 0.520829
2910274 | 지상 2층 | 지상 2층 | 2905462 | 1001.66 | 0.260415 | 0.0100166 | 0.520829
2910275 | 지상 2층 | 지상 2층 | 2905462 | 1001.66 | 0.260415 | 0.0100166 | 0.520829
2910276 | 지상 2층 | 지상 2층 | 2905462 | 650 | 0.1725 | 0.0065 | 0.335
2910277 | 지상 2층 | 지상 2층 | 2905462 | 600 | 0.16 | 0.006 | 0.3
2910278 | 지상 2층 | 지상 2층 | 2905462 | 1520 | 0.39 | 0.0152 | 0.77
2910346 | 지상 2층 | 지상 2층 | 2905462 | 350 | 0.0975 | 0.0035 | 0.175
2910347 | 지상 2층 | 지상 2층 | 2905462 | 650 | 0.1725 | 0.0065 | 0.335
2910348 | 지상 2층 | 지상 2층 | 2905462 | 912.5 | 0.238125 | 0.009125 | 0.47625
2910349 | 지상 2층 | 지상 2층 | 2905462 | 937.5 | 0.244375 | 0.009375 | 0.48875
2910350 | 지상 2층 | 지상 2층 | 2905462 | 937.5 | 0.244375 | 0.009375 | 0.48875
2910351 | 지상 2층 | 지상 2층 | 2905462 | 1001.66 | 0.260415 | 0.0100166 | 0.520829
2910352 | 지상 2층 | 지상 2층 | 2905462 | 350 | 0.0975 | 0.0035 | 0.175
2910353 | 지상 2층 | 지상 2층 | 2905462 | 350 | 0.0975 | 0.0035 | 0.175
2910354 | 지상 2층 | 지상 2층 | 2905462 | 350 | 0.0975 | 0.0035 | 0.175
2905551 | 지상 2층 | 지상 2층 | 2905548 | 729.167 | 0.192292 | 0.00729167 | 0.384583
2905552 | 지상 2층 | 지상 2층 | 2905548 | 811.167 | 0.212792 | 0.00811167 | 0.425583
2905553 | 지상 2층 | 지상 2층 | 2905548 | 650 | 0.1725 | 0.0065 | 0.335
2905554 | 지상 2층 | 지상 2층 | 2905548 | 1520 | 0.39 | 0.0152 | 0.77
2911093 | 지상 2층 | 지상 2층 | 2905548 | 1520 | 0.39 | 0.0152 | 0.77
2911094 | 지상 2층 | 지상 2층 | 2905548 | 600 | 0.16 | 0.006 | 0.3
2911095 | 지상 2층 | 지상 2층 | 2905548 | 811.167 | 0.212792 | 0.00811167 | 0.425583
2911158 | 지상 2층 | 지상 2층 | 2905548 | 811.167 | 0.212792 | 0.00811167 | 0.425583
2911159 | 지상 2층 | 지상 2층 | 2905548 | 754.167 | 0.198542 | 0.00754167 | 0.397083
2911160 | 지상 2층 | 지상 2층 | 2905548 | 754.167 | 0.198542 | 0.00754167 | 0.397083
2911161 | 지상 2층 | 지상 2층 | 2905548 | 650 | 0.1725 | 0.0065 | 0.335
2911162 | 지상 2층 | 지상 2층 | 2905548 | 1520 | 0.39 | 0.0152 | 0.77
2911244 | 지상 2층 | 지상 2층 | 2905548 | 754.167 | 0.198542 | 0.00754167 | 0.397083
2911245 | 지상 2층 | 지상 2층 | 2905548 | 754.167 | 0.198542 | 0.00754167 | 0.397083
2911246 | 지상 2층 | 지상 2층 | 2905548 | 754.167 | 0.198542 | 0.00754167 | 0.397083
2911247 | 지상 2층 | 지상 2층 | 2905548 | 650 | 0.1725 | 0.0065 | 0.335
2911248 | 지상 2층 | 지상 2층 | 2905548 | 1520 | 0.39 | 0.0152 | 0.77
2911332 | 지상 2층 | 지상 2층 | 2905548 | 754.167 | 0.198542 | 0.00754167 | 0.397083
2911333 | 지상 2층 | 지상 2층 | 2905548 | 754.167 | 0.198542 | 0.00754167 | 0.397083
2911334 | 지상 2층 | 지상 2층 | 2905548 | 754.167 | 0.198542 | 0.00754167 | 0.397083
2911335 | 지상 2층 | 지상 2층 | 2905548 | 650 | 0.1725 | 0.0065 | 0.335
2911336 | 지상 2층 | 지상 2층 | 2905548 | 1520 | 0.39 | 0.0152 | 0.77
2911408 | 지상 2층 | 지상 2층 | 2905548 | 754.167 | 0.198542 | 0.00754167 | 0.397083
2911409 | 지상 2층 | 지상 2층 | 2905548 | 754.167 | 0.198542 | 0.00754167 | 0.397083
2911410 | 지상 2층 | 지상 2층 | 2905548 | 754.167 | 0.198542 | 0.00754167 | 0.397083
2911411 | 지상 2층 | 지상 2층 | 2905548 | 650 | 0.1725 | 0.0065 | 0.335
2911412 | 지상 2층 | 지상 2층 | 2905548 | 1520 | 0.39 | 0.0152 | 0.77
2911480 | 지상 2층 | 지상 2층 | 2905548 | 754.167 | 0.198542 | 0.00754167 | 0.397083
2911481 | 지상 2층 | 지상 2층 | 2905548 | 729.167 | 0.192292 | 0.00729167 | 0.384583
2911482 | 지상 2층 | 지상 2층 | 2905548 | 729.167 | 0.192292 | 0.00729167 | 0.384583
2911483 | 지상 2층 | 지상 2층 | 2905548 | 650 | 0.1725 | 0.0065 | 0.335
2911484 | 지상 2층 | 지상 2층 | 2905548 | 1520 | 0.39 | 0.0152 | 0.77
2911591 | 지상 2층 | 지상 2층 | 2905548 | 600 | 0.16 | 0.006 | 0.3
2911592 | 지상 2층 | 지상 2층 | 2905548 | 350 | 0.0975 | 0.0035 | 0.175
2911593 | 지상 2층 | 지상 2층 | 2905548 | 811.167 | 0.212792 | 0.00811167 | 0.425583
2911594 | 지상 2층 | 지상 2층 | 2905548 | 754.167 | 0.198542 | 0.00754167 | 0.397083
2911595 | 지상 2층 | 지상 2층 | 2905548 | 754.167 | 0.198542 | 0.00754167 | 0.397083
2911596 | 지상 2층 | 지상 2층 | 2905548 | 754.167 | 0.198542 | 0.00754167 | 0.397083
2911597 | 지상 2층 | 지상 2층 | 2905548 | 754.167 | 0.198542 | 0.00754167 | 0.397083
2911598 | 지상 2층 | 지상 2층 | 2905548 | 729.167 | 0.192292 | 0.00729167 | 0.384583
2911599 | 지상 2층 | 지상 2층 | 2905548 | 600 | 0.16 | 0.006 | 0.3
2911600 | 지상 2층 | 지상 2층 | 2905548 | 600 | 0.16 | 0.006 | 0.3
2911601 | 지상 2층 | 지상 2층 | 2905548 | 600 | 0.16 | 0.006 | 0.3
2911602 | 지상 2층 | 지상 2층 | 2905548 | 600 | 0.16 | 0.006 | 0.3
2911603 | 지상 2층 | 지상 2층 | 2905548 | 600 | 0.16 | 0.006 | 0.3
2911686 | 지상 2층 | 지상 2층 | 2905548 | 350 | 0.0975 | 0.0035 | 0.175
2911687 | 지상 2층 | 지상 2층 | 2905548 | 650 | 0.1725 | 0.0065 | 0.335
2911688 | 지상 2층 | 지상 2층 | 2905548 | 811.167 | 0.212792 | 0.00811167 | 0.425583
2911689 | 지상 2층 | 지상 2층 | 2905548 | 754.167 | 0.198542 | 0.00754167 | 0.397083
2911690 | 지상 2층 | 지상 2층 | 2905548 | 754.167 | 0.198542 | 0.00754167 | 0.397083
2911691 | 지상 2층 | 지상 2층 | 2905548 | 754.167 | 0.198542 | 0.00754167 | 0.397083
2911692 | 지상 2층 | 지상 2층 | 2905548 | 754.167 | 0.198542 | 0.00754167 | 0.397083
2911693 | 지상 2층 | 지상 2층 | 2905548 | 729.167 | 0.192292 | 0.00729167 | 0.384583
2911694 | 지상 2층 | 지상 2층 | 2905548 | 350 | 0.0975 | 0.0035 | 0.175
2911695 | 지상 2층 | 지상 2층 | 2905548 | 350 | 0.0975 | 0.0035 | 0.175
2911696 | 지상 2층 | 지상 2층 | 2905548 | 350 | 0.0975 | 0.0035 | 0.175
2911697 | 지상 2층 | 지상 2층 | 2905548 | 350 | 0.0975 | 0.0035 | 0.175
2911698 | 지상 2층 | 지상 2층 | 2905548 | 350 | 0.0975 | 0.0035 | 0.175
2905637 | 지상 2층 | 지상 2층 | 2905633 | 811.167 | 0.212792 | 0.00811167 | 0.425583
2905638 | 지상 2층 | 지상 2층 | 2905633 | 729.167 | 0.192292 | 0.00729167 | 0.384583
2905639 | 지상 2층 | 지상 2층 | 2905633 | 650 | 0.1725 | 0.0065 | 0.335
2905640 | 지상 2층 | 지상 2층 | 2905633 | 1520 | 0.39 | 0.0152 | 0.77
2912028 | 지상 2층 | 지상 2층 | 2905633 | 1520 | 0.39 | 0.0152 | 0.77
2912029 | 지상 2층 | 지상 2층 | 2905633 | 600 | 0.16 | 0.006 | 0.3
2912030 | 지상 2층 | 지상 2층 | 2905633 | 729.167 | 0.192292 | 0.00729167 | 0.384583
2912133 | 지상 2층 | 지상 2층 | 2905633 | 729.167 | 0.192292 | 0.00729167 | 0.384583
2912134 | 지상 2층 | 지상 2층 | 2905633 | 754.167 | 0.198542 | 0.00754167 | 0.397083
2912135 | 지상 2층 | 지상 2층 | 2905633 | 754.167 | 0.198542 | 0.00754167 | 0.397083
2912136 | 지상 2층 | 지상 2층 | 2905633 | 650 | 0.1725 | 0.0065 | 0.335
2912137 | 지상 2층 | 지상 2층 | 2905633 | 1520 | 0.39 | 0.0152 | 0.77
2912218 | 지상 2층 | 지상 2층 | 2905633 | 754.167 | 0.198542 | 0.00754167 | 0.397083
2912219 | 지상 2층 | 지상 2층 | 2905633 | 754.167 | 0.198542 | 0.00754167 | 0.397083
2912220 | 지상 2층 | 지상 2층 | 2905633 | 754.167 | 0.198542 | 0.00754167 | 0.397083
2912221 | 지상 2층 | 지상 2층 | 2905633 | 650 | 0.1725 | 0.0065 | 0.335
2912222 | 지상 2층 | 지상 2층 | 2905633 | 1520 | 0.39 | 0.0152 | 0.77
2912272 | 지상 2층 | 지상 2층 | 2905633 | 754.167 | 0.198542 | 0.00754167 | 0.397083
2912273 | 지상 2층 | 지상 2층 | 2905633 | 754.167 | 0.198542 | 0.00754167 | 0.397083
2912274 | 지상 2층 | 지상 2층 | 2905633 | 754.167 | 0.198542 | 0.00754167 | 0.397083
2912275 | 지상 2층 | 지상 2층 | 2905633 | 650 | 0.1725 | 0.0065 | 0.335
2912276 | 지상 2층 | 지상 2층 | 2905633 | 1520 | 0.39 | 0.0152 | 0.77
2912336 | 지상 2층 | 지상 2층 | 2905633 | 754.167 | 0.198542 | 0.00754167 | 0.397083
2912337 | 지상 2층 | 지상 2층 | 2905633 | 754.167 | 0.198542 | 0.00754167 | 0.397083
2912338 | 지상 2층 | 지상 2층 | 2905633 | 754.167 | 0.198542 | 0.00754167 | 0.397083
2912339 | 지상 2층 | 지상 2층 | 2905633 | 650 | 0.1725 | 0.0065 | 0.335
2912340 | 지상 2층 | 지상 2층 | 2905633 | 1520 | 0.39 | 0.0152 | 0.77
2912406 | 지상 2층 | 지상 2층 | 2905633 | 754.167 | 0.198542 | 0.00754167 | 0.397083
2912407 | 지상 2층 | 지상 2층 | 2905633 | 811.167 | 0.212792 | 0.00811167 | 0.425583
2912408 | 지상 2층 | 지상 2층 | 2905633 | 811.167 | 0.212792 | 0.00811167 | 0.425583
2912409 | 지상 2층 | 지상 2층 | 2905633 | 650 | 0.1725 | 0.0065 | 0.335
2912410 | 지상 2층 | 지상 2층 | 2905633 | 1520 | 0.39 | 0.0152 | 0.77
2912479 | 지상 2층 | 지상 2층 | 2905633 | 350 | 0.0975 | 0.0035 | 0.175
2912480 | 지상 2층 | 지상 2층 | 2905633 | 650 | 0.1725 | 0.0065 | 0.335
2912481 | 지상 2층 | 지상 2층 | 2905633 | 729.167 | 0.192292 | 0.00729167 | 0.384583
2912482 | 지상 2층 | 지상 2층 | 2905633 | 754.167 | 0.198542 | 0.00754167 | 0.397083
2912483 | 지상 2층 | 지상 2층 | 2905633 | 754.167 | 0.198542 | 0.00754167 | 0.397083
2912484 | 지상 2층 | 지상 2층 | 2905633 | 754.167 | 0.198542 | 0.00754167 | 0.397083
2912485 | 지상 2층 | 지상 2층 | 2905633 | 754.167 | 0.198542 | 0.00754167 | 0.397083
2912486 | 지상 2층 | 지상 2층 | 2905633 | 811.167 | 0.212792 | 0.00811167 | 0.425583
2912487 | 지상 2층 | 지상 2층 | 2905633 | 350 | 0.0975 | 0.0035 | 0.175
2912488 | 지상 2층 | 지상 2층 | 2905633 | 350 | 0.0975 | 0.0035 | 0.175
2912489 | 지상 2층 | 지상 2층 | 2905633 | 350 | 0.0975 | 0.0035 | 0.175
2912490 | 지상 2층 | 지상 2층 | 2905633 | 350 | 0.0975 | 0.0035 | 0.175
2912491 | 지상 2층 | 지상 2층 | 2905633 | 350 | 0.0975 | 0.0035 | 0.175
2912553 | 지상 2층 | 지상 2층 | 2905633 | 600 | 0.16 | 0.006 | 0.3
2912554 | 지상 2층 | 지상 2층 | 2905633 | 350 | 0.0975 | 0.0035 | 0.175
2912555 | 지상 2층 | 지상 2층 | 2905633 | 729.167 | 0.192292 | 0.00729167 | 0.384583
2912556 | 지상 2층 | 지상 2층 | 2905633 | 754.167 | 0.198542 | 0.00754167 | 0.397083
2912557 | 지상 2층 | 지상 2층 | 2905633 | 754.167 | 0.198542 | 0.00754167 | 0.397083
2912558 | 지상 2층 | 지상 2층 | 2905633 | 754.167 | 0.198542 | 0.00754167 | 0.397083
2912559 | 지상 2층 | 지상 2층 | 2905633 | 754.167 | 0.198542 | 0.00754167 | 0.397083
2912560 | 지상 2층 | 지상 2층 | 2905633 | 811.167 | 0.212792 | 0.00811167 | 0.425583
2912561 | 지상 2층 | 지상 2층 | 2905633 | 600 | 0.16 | 0.006 | 0.3
2912562 | 지상 2층 | 지상 2층 | 2905633 | 600 | 0.16 | 0.006 | 0.3
2912563 | 지상 2층 | 지상 2층 | 2905633 | 600 | 0.16 | 0.006 | 0.3
2912564 | 지상 2층 | 지상 2층 | 2905633 | 600 | 0.16 | 0.006 | 0.3
2912565 | 지상 2층 | 지상 2층 | 2905633 | 600 | 0.16 | 0.006 | 0.3
2905751 | 지상 2층 | 지상 2층 | 2905747 | 806.25 | 0.211563 | 0.0080625 | 0.423125
2905752 | 지상 2층 | 지상 2층 | 2905747 | 838.25 | 0.219562 | 0.0083825 | 0.439125
2905753 | 지상 2층 | 지상 2층 | 2905747 | 650 | 0.1725 | 0.0065 | 0.335
2905754 | 지상 2층 | 지상 2층 | 2905747 | 1520 | 0.39 | 0.0152 | 0.77
2912903 | 지상 2층 | 지상 2층 | 2905747 | 838.25 | 0.219562 | 0.0083825 | 0.439125
2912904 | 지상 2층 | 지상 2층 | 2905747 | 731.25 | 0.192812 | 0.0073125 | 0.385625
2912905 | 지상 2층 | 지상 2층 | 2905747 | 650 | 0.1725 | 0.0065 | 0.335
2912997 | 지상 2층 | 지상 2층 | 2905747 | 1520 | 0.39 | 0.0152 | 0.77
2912998 | 지상 2층 | 지상 2층 | 2905747 | 600 | 0.16 | 0.006 | 0.3
2912999 | 지상 2층 | 지상 2층 | 2905747 | 838.25 | 0.219562 | 0.0083825 | 0.439125
2913000 | 지상 2층 | 지상 2층 | 2905747 | 731.25 | 0.192812 | 0.0073125 | 0.385625
2913001 | 지상 2층 | 지상 2층 | 2905747 | 1520 | 0.39 | 0.0152 | 0.77
2913075 | 지상 2층 | 지상 2층 | 2905747 | 731.25 | 0.192812 | 0.0073125 | 0.385625
2913076 | 지상 2층 | 지상 2층 | 2905747 | 731.25 | 0.192812 | 0.0073125 | 0.385625
2913077 | 지상 2층 | 지상 2층 | 2905747 | 731.25 | 0.192812 | 0.0073125 | 0.385625
2913078 | 지상 2층 | 지상 2층 | 2905747 | 650 | 0.1725 | 0.0065 | 0.335
2913079 | 지상 2층 | 지상 2층 | 2905747 | 1520 | 0.39 | 0.0152 | 0.77
2913140 | 지상 2층 | 지상 2층 | 2905747 | 731.25 | 0.192812 | 0.0073125 | 0.385625
2913141 | 지상 2층 | 지상 2층 | 2905747 | 731.25 | 0.192812 | 0.0073125 | 0.385625
2913142 | 지상 2층 | 지상 2층 | 2905747 | 731.25 | 0.192812 | 0.0073125 | 0.385625
2913143 | 지상 2층 | 지상 2층 | 2905747 | 650 | 0.1725 | 0.0065 | 0.335
2913144 | 지상 2층 | 지상 2층 | 2905747 | 1520 | 0.39 | 0.0152 | 0.77
2913209 | 지상 2층 | 지상 2층 | 2905747 | 731.25 | 0.192812 | 0.0073125 | 0.385625
2913210 | 지상 2층 | 지상 2층 | 2905747 | 731.25 | 0.192812 | 0.0073125 | 0.385625
2913211 | 지상 2층 | 지상 2층 | 2905747 | 731.25 | 0.192812 | 0.0073125 | 0.385625
2913212 | 지상 2층 | 지상 2층 | 2905747 | 650 | 0.1725 | 0.0065 | 0.335
2913213 | 지상 2층 | 지상 2층 | 2905747 | 1520 | 0.39 | 0.0152 | 0.77
2913269 | 지상 2층 | 지상 2층 | 2905747 | 731.25 | 0.192812 | 0.0073125 | 0.385625
2913270 | 지상 2층 | 지상 2층 | 2905747 | 731.25 | 0.192812 | 0.0073125 | 0.385625
2913271 | 지상 2층 | 지상 2층 | 2905747 | 731.25 | 0.192812 | 0.0073125 | 0.385625
2913272 | 지상 2층 | 지상 2층 | 2905747 | 650 | 0.1725 | 0.0065 | 0.335
2913273 | 지상 2층 | 지상 2층 | 2905747 | 1520 | 0.39 | 0.0152 | 0.77
2913329 | 지상 2층 | 지상 2층 | 2905747 | 600 | 0.16 | 0.006 | 0.3
2913330 | 지상 2층 | 지상 2층 | 2905747 | 350 | 0.0975 | 0.0035 | 0.175
2913331 | 지상 2층 | 지상 2층 | 2905747 | 838.25 | 0.219562 | 0.0083825 | 0.439125
2913332 | 지상 2층 | 지상 2층 | 2905747 | 731.25 | 0.192812 | 0.0073125 | 0.385625
2913333 | 지상 2층 | 지상 2층 | 2905747 | 731.25 | 0.192812 | 0.0073125 | 0.385625
2913334 | 지상 2층 | 지상 2층 | 2905747 | 731.25 | 0.192812 | 0.0073125 | 0.385625
2913335 | 지상 2층 | 지상 2층 | 2905747 | 731.25 | 0.192812 | 0.0073125 | 0.385625
2913336 | 지상 2층 | 지상 2층 | 2905747 | 731.25 | 0.192812 | 0.0073125 | 0.385625
2913337 | 지상 2층 | 지상 2층 | 2905747 | 600 | 0.16 | 0.006 | 0.3
2913338 | 지상 2층 | 지상 2층 | 2905747 | 600 | 0.16 | 0.006 | 0.3
2913339 | 지상 2층 | 지상 2층 | 2905747 | 600 | 0.16 | 0.006 | 0.3
2913340 | 지상 2층 | 지상 2층 | 2905747 | 600 | 0.16 | 0.006 | 0.3
2913341 | 지상 2층 | 지상 2층 | 2905747 | 600 | 0.16 | 0.006 | 0.3
2913401 | 지상 2층 | 지상 2층 | 2905747 | 731.25 | 0.192812 | 0.0073125 | 0.385625
2913402 | 지상 2층 | 지상 2층 | 2905747 | 731.25 | 0.192812 | 0.0073125 | 0.385625
2913403 | 지상 2층 | 지상 2층 | 2905747 | 731.25 | 0.192812 | 0.0073125 | 0.385625
2913404 | 지상 2층 | 지상 2층 | 2905747 | 731.25 | 0.192812 | 0.0073125 | 0.385625
2913405 | 지상 2층 | 지상 2층 | 2905747 | 650 | 0.1725 | 0.0065 | 0.335
2913406 | 지상 2층 | 지상 2층 | 2905747 | 600 | 0.16 | 0.006 | 0.3
2913407 | 지상 2층 | 지상 2층 | 2905747 | 1520 | 0.39 | 0.0152 | 0.77
2913501 | 지상 2층 | 지상 2층 | 2905747 | 731.25 | 0.192812 | 0.0073125 | 0.385625
2913502 | 지상 2층 | 지상 2층 | 2905747 | 806.25 | 0.211563 | 0.0080625 | 0.423125
2913503 | 지상 2층 | 지상 2층 | 2905747 | 806.25 | 0.211563 | 0.0080625 | 0.423125
2913504 | 지상 2층 | 지상 2층 | 2905747 | 806.25 | 0.211563 | 0.0080625 | 0.423125
2913505 | 지상 2층 | 지상 2층 | 2905747 | 650 | 0.1725 | 0.0065 | 0.335
2913506 | 지상 2층 | 지상 2층 | 2905747 | 600 | 0.16 | 0.006 | 0.3
2913507 | 지상 2층 | 지상 2층 | 2905747 | 1520 | 0.39 | 0.0152 | 0.77
2913584 | 지상 2층 | 지상 2층 | 2905747 | 350 | 0.0975 | 0.0035 | 0.175
2913585 | 지상 2층 | 지상 2층 | 2905747 | 650 | 0.1725 | 0.0065 | 0.335
2913586 | 지상 2층 | 지상 2층 | 2905747 | 838.25 | 0.219562 | 0.0083825 | 0.439125
2913587 | 지상 2층 | 지상 2층 | 2905747 | 731.25 | 0.192812 | 0.0073125 | 0.385625
2913588 | 지상 2층 | 지상 2층 | 2905747 | 731.25 | 0.192812 | 0.0073125 | 0.385625
2913589 | 지상 2층 | 지상 2층 | 2905747 | 731.25 | 0.192812 | 0.0073125 | 0.385625
2913590 | 지상 2층 | 지상 2층 | 2905747 | 731.25 | 0.192812 | 0.0073125 | 0.385625
2913591 | 지상 2층 | 지상 2층 | 2905747 | 731.25 | 0.192812 | 0.0073125 | 0.385625
2913592 | 지상 2층 | 지상 2층 | 2905747 | 731.25 | 0.192812 | 0.0073125 | 0.385625
2913593 | 지상 2층 | 지상 2층 | 2905747 | 806.25 | 0.211563 | 0.0080625 | 0.423125
2913594 | 지상 2층 | 지상 2층 | 2905747 | 350 | 0.0975 | 0.0035 | 0.175
2913595 | 지상 2층 | 지상 2층 | 2905747 | 350 | 0.0975 | 0.0035 | 0.175
2913596 | 지상 2층 | 지상 2층 | 2905747 | 350 | 0.0975 | 0.0035 | 0.175
2913597 | 지상 2층 | 지상 2층 | 2905747 | 350 | 0.0975 | 0.0035 | 0.175
2913598 | 지상 2층 | 지상 2층 | 2905747 | 350 | 0.0975 | 0.0035 | 0.175
2913599 | 지상 2층 | 지상 2층 | 2905747 | 350 | 0.0975 | 0.0035 | 0.175
2913600 | 지상 2층 | 지상 2층 | 2905747 | 350 | 0.0975 | 0.0035 | 0.175
2905906 | 지상 2층 | 지상 2층 | 2905902 | 810 | 0.2125 | 0.0081 | 0.425
2905907 | 지상 2층 | 지상 2층 | 2905902 | 860 | 0.225 | 0.0086 | 0.45
2905908 | 지상 2층 | 지상 2층 | 2905902 | 650 | 0.1725 | 0.0065 | 0.335
2905909 | 지상 2층 | 지상 2층 | 2905902 | 1520 | 0.39 | 0.0152 | 0.77
2913938 | 지상 2층 | 지상 2층 | 2905902 | 860 | 0.225 | 0.0086 | 0.45
2913939 | 지상 2층 | 지상 2층 | 2905902 | 735 | 0.19375 | 0.00735 | 0.3875
2913940 | 지상 2층 | 지상 2층 | 2905902 | 650 | 0.1725 | 0.0065 | 0.335
2913990 | 지상 2층 | 지상 2층 | 2905902 | 1520 | 0.39 | 0.0152 | 0.77
2913991 | 지상 2층 | 지상 2층 | 2905902 | 600 | 0.16 | 0.006 | 0.3
2913992 | 지상 2층 | 지상 2층 | 2905902 | 860 | 0.225 | 0.0086 | 0.45
2913993 | 지상 2층 | 지상 2층 | 2905902 | 735 | 0.19375 | 0.00735 | 0.3875
2913994 | 지상 2층 | 지상 2층 | 2905902 | 1520 | 0.39 | 0.0152 | 0.77
2914060 | 지상 2층 | 지상 2층 | 2905902 | 735 | 0.19375 | 0.00735 | 0.3875
2914061 | 지상 2층 | 지상 2층 | 2905902 | 735 | 0.19375 | 0.00735 | 0.3875
2914062 | 지상 2층 | 지상 2층 | 2905902 | 735 | 0.19375 | 0.00735 | 0.3875
2914063 | 지상 2층 | 지상 2층 | 2905902 | 650 | 0.1725 | 0.0065 | 0.335
2914064 | 지상 2층 | 지상 2층 | 2905902 | 1520 | 0.39 | 0.0152 | 0.77
2914127 | 지상 2층 | 지상 2층 | 2905902 | 735 | 0.19375 | 0.00735 | 0.3875
2914128 | 지상 2층 | 지상 2층 | 2905902 | 735 | 0.19375 | 0.00735 | 0.3875
2914129 | 지상 2층 | 지상 2층 | 2905902 | 735 | 0.19375 | 0.00735 | 0.3875
2914130 | 지상 2층 | 지상 2층 | 2905902 | 650 | 0.1725 | 0.0065 | 0.335
2914131 | 지상 2층 | 지상 2층 | 2905902 | 1520 | 0.39 | 0.0152 | 0.77
2914207 | 지상 2층 | 지상 2층 | 2905902 | 735 | 0.19375 | 0.00735 | 0.3875
2914208 | 지상 2층 | 지상 2층 | 2905902 | 735 | 0.19375 | 0.00735 | 0.3875
2914209 | 지상 2층 | 지상 2층 | 2905902 | 735 | 0.19375 | 0.00735 | 0.3875
2914210 | 지상 2층 | 지상 2층 | 2905902 | 650 | 0.1725 | 0.0065 | 0.335
2914211 | 지상 2층 | 지상 2층 | 2905902 | 1520 | 0.39 | 0.0152 | 0.77
2914266 | 지상 2층 | 지상 2층 | 2905902 | 735 | 0.19375 | 0.00735 | 0.3875
2914267 | 지상 2층 | 지상 2층 | 2905902 | 735 | 0.19375 | 0.00735 | 0.3875
2914268 | 지상 2층 | 지상 2층 | 2905902 | 735 | 0.19375 | 0.00735 | 0.3875
2914269 | 지상 2층 | 지상 2층 | 2905902 | 650 | 0.1725 | 0.0065 | 0.335
2914270 | 지상 2층 | 지상 2층 | 2905902 | 1520 | 0.39 | 0.0152 | 0.77
2914332 | 지상 2층 | 지상 2층 | 2905902 | 735 | 0.19375 | 0.00735 | 0.3875
2914333 | 지상 2층 | 지상 2층 | 2905902 | 735 | 0.19375 | 0.00735 | 0.3875
2914334 | 지상 2층 | 지상 2층 | 2905902 | 735 | 0.19375 | 0.00735 | 0.3875
2914335 | 지상 2층 | 지상 2층 | 2905902 | 650 | 0.1725 | 0.0065 | 0.335
2914336 | 지상 2층 | 지상 2층 | 2905902 | 1520 | 0.39 | 0.0152 | 0.77
2914375 | 지상 2층 | 지상 2층 | 2905902 | 735 | 0.19375 | 0.00735 | 0.3875
2914376 | 지상 2층 | 지상 2층 | 2905902 | 735 | 0.19375 | 0.00735 | 0.3875
2914377 | 지상 2층 | 지상 2층 | 2905902 | 735 | 0.19375 | 0.00735 | 0.3875
2914378 | 지상 2층 | 지상 2층 | 2905902 | 650 | 0.1725 | 0.0065 | 0.335
2914379 | 지상 2층 | 지상 2층 | 2905902 | 1520 | 0.39 | 0.0152 | 0.77
2914431 | 지상 2층 | 지상 2층 | 2905902 | 735 | 0.19375 | 0.00735 | 0.3875
2914432 | 지상 2층 | 지상 2층 | 2905902 | 735 | 0.19375 | 0.00735 | 0.3875
2914433 | 지상 2층 | 지상 2층 | 2905902 | 735 | 0.19375 | 0.00735 | 0.3875
2914434 | 지상 2층 | 지상 2층 | 2905902 | 650 | 0.1725 | 0.0065 | 0.335
2914435 | 지상 2층 | 지상 2층 | 2905902 | 1520 | 0.39 | 0.0152 | 0.77
2914494 | 지상 2층 | 지상 2층 | 2905902 | 735 | 0.19375 | 0.00735 | 0.3875
2914495 | 지상 2층 | 지상 2층 | 2905902 | 810 | 0.2125 | 0.0081 | 0.425
2914496 | 지상 2층 | 지상 2층 | 2905902 | 810 | 0.2125 | 0.0081 | 0.425
2914497 | 지상 2층 | 지상 2층 | 2905902 | 650 | 0.1725 | 0.0065 | 0.335
2914498 | 지상 2층 | 지상 2층 | 2905902 | 1520 | 0.39 | 0.0152 | 0.77
2914559 | 지상 2층 | 지상 2층 | 2905902 | 600 | 0.16 | 0.006 | 0.3
2914560 | 지상 2층 | 지상 2층 | 2905902 | 350 | 0.0975 | 0.0035 | 0.175
2914561 | 지상 2층 | 지상 2층 | 2905902 | 860 | 0.225 | 0.0086 | 0.45
2914562 | 지상 2층 | 지상 2층 | 2905902 | 735 | 0.19375 | 0.00735 | 0.3875
2914563 | 지상 2층 | 지상 2층 | 2905902 | 735 | 0.19375 | 0.00735 | 0.3875
2914564 | 지상 2층 | 지상 2층 | 2905902 | 735 | 0.19375 | 0.00735 | 0.3875
2914565 | 지상 2층 | 지상 2층 | 2905902 | 735 | 0.19375 | 0.00735 | 0.3875
2914566 | 지상 2층 | 지상 2층 | 2905902 | 735 | 0.19375 | 0.00735 | 0.3875
2914567 | 지상 2층 | 지상 2층 | 2905902 | 735 | 0.19375 | 0.00735 | 0.3875
2914568 | 지상 2층 | 지상 2층 | 2905902 | 735 | 0.19375 | 0.00735 | 0.3875
2914569 | 지상 2층 | 지상 2층 | 2905902 | 735 | 0.19375 | 0.00735 | 0.3875
2914570 | 지상 2층 | 지상 2층 | 2905902 | 810 | 0.2125 | 0.0081 | 0.425
2914571 | 지상 2층 | 지상 2층 | 2905902 | 600 | 0.16 | 0.006 | 0.3
2914572 | 지상 2층 | 지상 2층 | 2905902 | 600 | 0.16 | 0.006 | 0.3
2914573 | 지상 2층 | 지상 2층 | 2905902 | 600 | 0.16 | 0.006 | 0.3
2914574 | 지상 2층 | 지상 2층 | 2905902 | 600 | 0.16 | 0.006 | 0.3
2914575 | 지상 2층 | 지상 2층 | 2905902 | 600 | 0.16 | 0.006 | 0.3
2914576 | 지상 2층 | 지상 2층 | 2905902 | 600 | 0.16 | 0.006 | 0.3
2914577 | 지상 2층 | 지상 2층 | 2905902 | 600 | 0.16 | 0.006 | 0.3
2914578 | 지상 2층 | 지상 2층 | 2905902 | 600 | 0.16 | 0.006 | 0.3
2914579 | 지상 2층 | 지상 2층 | 2905902 | 600 | 0.16 | 0.006 | 0.3
2914657 | 지상 2층 | 지상 2층 | 2905902 | 350 | 0.0975 | 0.0035 | 0.175
2914658 | 지상 2층 | 지상 2층 | 2905902 | 650 | 0.1725 | 0.0065 | 0.335
2914659 | 지상 2층 | 지상 2층 | 2905902 | 860 | 0.225 | 0.0086 | 0.45
2914660 | 지상 2층 | 지상 2층 | 2905902 | 735 | 0.19375 | 0.00735 | 0.3875
2914661 | 지상 2층 | 지상 2층 | 2905902 | 735 | 0.19375 | 0.00735 | 0.3875
2914662 | 지상 2층 | 지상 2층 | 2905902 | 735 | 0.19375 | 0.00735 | 0.3875
2914663 | 지상 2층 | 지상 2층 | 2905902 | 735 | 0.19375 | 0.00735 | 0.3875
2914664 | 지상 2층 | 지상 2층 | 2905902 | 735 | 0.19375 | 0.00735 | 0.3875
2914665 | 지상 2층 | 지상 2층 | 2905902 | 735 | 0.19375 | 0.00735 | 0.3875
2914666 | 지상 2층 | 지상 2층 | 2905902 | 735 | 0.19375 | 0.00735 | 0.3875
2914667 | 지상 2층 | 지상 2층 | 2905902 | 735 | 0.19375 | 0.00735 | 0.3875
2914668 | 지상 2층 | 지상 2층 | 2905902 | 810 | 0.2125 | 0.0081 | 0.425
2914669 | 지상 2층 | 지상 2층 | 2905902 | 350 | 0.0975 | 0.0035 | 0.175
2914670 | 지상 2층 | 지상 2층 | 2905902 | 350 | 0.0975 | 0.0035 | 0.175
2914671 | 지상 2층 | 지상 2층 | 2905902 | 350 | 0.0975 | 0.0035 | 0.175
2914672 | 지상 2층 | 지상 2층 | 2905902 | 350 | 0.0975 | 0.0035 | 0.175
2914673 | 지상 2층 | 지상 2층 | 2905902 | 350 | 0.0975 | 0.0035 | 0.175
2914674 | 지상 2층 | 지상 2층 | 2905902 | 350 | 0.0975 | 0.0035 | 0.175
2914675 | 지상 2층 | 지상 2층 | 2905902 | 350 | 0.0975 | 0.0035 | 0.175
2914676 | 지상 2층 | 지상 2층 | 2905902 | 350 | 0.0975 | 0.0035 | 0.175
2914677 | 지상 2층 | 지상 2층 | 2905902 | 350 | 0.0975 | 0.0035 | 0.175
2914931 | 지상 2층 | 지상 2층 | 2914928 | 913.889 | 0.238472 | 0.00913889 | 0.476944
2914932 | 지상 2층 | 지상 2층 | 2914928 | 984.323 | 0.256081 | 0.00984323 | 0.512162
2914933 | 지상 2층 | 지상 2층 | 2914928 | 650 | 0.1725 | 0.0065 | 0.335
2914934 | 지상 2층 | 지상 2층 | 2914928 | 1520 | 0.39 | 0.0152 | 0.77
2915246 | 지상 2층 | 지상 2층 | 2914928 | 984.323 | 0.256081 | 0.00984323 | 0.512162
2915247 | 지상 2층 | 지상 2층 | 2914928 | 938.889 | 0.244722 | 0.00938889 | 0.489444
2915248 | 지상 2층 | 지상 2층 | 2914928 | 650 | 0.1725 | 0.0065 | 0.335
2915296 | 지상 2층 | 지상 2층 | 2914928 | 1520 | 0.39 | 0.0152 | 0.77
2915297 | 지상 2층 | 지상 2층 | 2914928 | 600 | 0.16 | 0.006 | 0.3
2915298 | 지상 2층 | 지상 2층 | 2914928 | 984.323 | 0.256081 | 0.00984323 | 0.512162
2915299 | 지상 2층 | 지상 2층 | 2914928 | 938.889 | 0.244722 | 0.00938889 | 0.489444
2915300 | 지상 2층 | 지상 2층 | 2914928 | 1520 | 0.39 | 0.0152 | 0.77
2915366 | 지상 2층 | 지상 2층 | 2914928 | 938.889 | 0.244722 | 0.00938889 | 0.489444
2915367 | 지상 2층 | 지상 2층 | 2914928 | 938.889 | 0.244722 | 0.00938889 | 0.489444
2915368 | 지상 2층 | 지상 2층 | 2914928 | 938.889 | 0.244722 | 0.00938889 | 0.489444
2915369 | 지상 2층 | 지상 2층 | 2914928 | 650 | 0.1725 | 0.0065 | 0.335
2915370 | 지상 2층 | 지상 2층 | 2914928 | 1520 | 0.39 | 0.0152 | 0.77
2915450 | 지상 2층 | 지상 2층 | 2914928 | 938.889 | 0.244722 | 0.00938889 | 0.489444
2915451 | 지상 2층 | 지상 2층 | 2914928 | 938.889 | 0.244722 | 0.00938889 | 0.489444
2915452 | 지상 2층 | 지상 2층 | 2914928 | 938.889 | 0.244722 | 0.00938889 | 0.489444
2915453 | 지상 2층 | 지상 2층 | 2914928 | 650 | 0.1725 | 0.0065 | 0.335
2915454 | 지상 2층 | 지상 2층 | 2914928 | 1520 | 0.39 | 0.0152 | 0.77
2915565 | 지상 2층 | 지상 2층 | 2914928 | 938.889 | 0.244722 | 0.00938889 | 0.489444
2915566 | 지상 2층 | 지상 2층 | 2914928 | 938.889 | 0.244722 | 0.00938889 | 0.489444
2915567 | 지상 2층 | 지상 2층 | 2914928 | 938.889 | 0.244722 | 0.00938889 | 0.489444
2915568 | 지상 2층 | 지상 2층 | 2914928 | 650 | 0.1725 | 0.0065 | 0.335
2915569 | 지상 2층 | 지상 2층 | 2914928 | 1520 | 0.39 | 0.0152 | 0.77
2915671 | 지상 2층 | 지상 2층 | 2914928 | 938.889 | 0.244722 | 0.00938889 | 0.489444
2915672 | 지상 2층 | 지상 2층 | 2914928 | 938.889 | 0.244722 | 0.00938889 | 0.489444
2915673 | 지상 2층 | 지상 2층 | 2914928 | 938.889 | 0.244722 | 0.00938889 | 0.489444
2915674 | 지상 2층 | 지상 2층 | 2914928 | 650 | 0.1725 | 0.0065 | 0.335
2915675 | 지상 2층 | 지상 2층 | 2914928 | 1520 | 0.39 | 0.0152 | 0.77
2915739 | 지상 2층 | 지상 2층 | 2914928 | 938.889 | 0.244722 | 0.00938889 | 0.489444
2915740 | 지상 2층 | 지상 2층 | 2914928 | 938.889 | 0.244722 | 0.00938889 | 0.489444
2915741 | 지상 2층 | 지상 2층 | 2914928 | 938.889 | 0.244722 | 0.00938889 | 0.489444
2915742 | 지상 2층 | 지상 2층 | 2914928 | 650 | 0.1725 | 0.0065 | 0.335
2915743 | 지상 2층 | 지상 2층 | 2914928 | 1520 | 0.39 | 0.0152 | 0.77
2915805 | 지상 2층 | 지상 2층 | 2914928 | 938.889 | 0.244722 | 0.00938889 | 0.489444
2915806 | 지상 2층 | 지상 2층 | 2914928 | 938.889 | 0.244722 | 0.00938889 | 0.489444
2915807 | 지상 2층 | 지상 2층 | 2914928 | 938.889 | 0.244722 | 0.00938889 | 0.489444
2915808 | 지상 2층 | 지상 2층 | 2914928 | 650 | 0.1725 | 0.0065 | 0.335
2915809 | 지상 2층 | 지상 2층 | 2914928 | 1520 | 0.39 | 0.0152 | 0.77
2915867 | 지상 2층 | 지상 2층 | 2914928 | 938.889 | 0.244722 | 0.00938889 | 0.489444
2915868 | 지상 2층 | 지상 2층 | 2914928 | 913.889 | 0.238472 | 0.00913889 | 0.476944
2915869 | 지상 2층 | 지상 2층 | 2914928 | 913.889 | 0.238472 | 0.00913889 | 0.476944
2915870 | 지상 2층 | 지상 2층 | 2914928 | 650 | 0.1725 | 0.0065 | 0.335
2915871 | 지상 2층 | 지상 2층 | 2914928 | 1520 | 0.39 | 0.0152 | 0.77
2915956 | 지상 2층 | 지상 2층 | 2914928 | 600 | 0.16 | 0.006 | 0.3
2915957 | 지상 2층 | 지상 2층 | 2914928 | 350 | 0.0975 | 0.0035 | 0.175
2915958 | 지상 2층 | 지상 2층 | 2914928 | 984.323 | 0.256081 | 0.00984323 | 0.512162
2915959 | 지상 2층 | 지상 2층 | 2914928 | 938.889 | 0.244722 | 0.00938889 | 0.489444
2915960 | 지상 2층 | 지상 2층 | 2914928 | 938.889 | 0.244722 | 0.00938889 | 0.489444
2915961 | 지상 2층 | 지상 2층 | 2914928 | 938.889 | 0.244722 | 0.00938889 | 0.489444
2915962 | 지상 2층 | 지상 2층 | 2914928 | 938.889 | 0.244722 | 0.00938889 | 0.489444
2915963 | 지상 2층 | 지상 2층 | 2914928 | 938.889 | 0.244722 | 0.00938889 | 0.489444
2915964 | 지상 2층 | 지상 2층 | 2914928 | 938.889 | 0.244722 | 0.00938889 | 0.489444
2915965 | 지상 2층 | 지상 2층 | 2914928 | 938.889 | 0.244722 | 0.00938889 | 0.489444
2915966 | 지상 2층 | 지상 2층 | 2914928 | 913.889 | 0.238472 | 0.00913889 | 0.476944
2915967 | 지상 2층 | 지상 2층 | 2914928 | 600 | 0.16 | 0.006 | 0.3
2915968 | 지상 2층 | 지상 2층 | 2914928 | 600 | 0.16 | 0.006 | 0.3
2915969 | 지상 2층 | 지상 2층 | 2914928 | 600 | 0.16 | 0.006 | 0.3
2915970 | 지상 2층 | 지상 2층 | 2914928 | 600 | 0.16 | 0.006 | 0.3
2915971 | 지상 2층 | 지상 2층 | 2914928 | 600 | 0.16 | 0.006 | 0.3
2915972 | 지상 2층 | 지상 2층 | 2914928 | 600 | 0.16 | 0.006 | 0.3
2915973 | 지상 2층 | 지상 2층 | 2914928 | 600 | 0.16 | 0.006 | 0.3
2915974 | 지상 2층 | 지상 2층 | 2914928 | 600 | 0.16 | 0.006 | 0.3
2916033 | 지상 2층 | 지상 2층 | 2914928 | 350 | 0.0975 | 0.0035 | 0.175
2916034 | 지상 2층 | 지상 2층 | 2914928 | 650 | 0.1725 | 0.0065 | 0.335
2916035 | 지상 2층 | 지상 2층 | 2914928 | 984.323 | 0.256081 | 0.00984323 | 0.512162
2916036 | 지상 2층 | 지상 2층 | 2914928 | 938.889 | 0.244722 | 0.00938889 | 0.489444
2916037 | 지상 2층 | 지상 2층 | 2914928 | 938.889 | 0.244722 | 0.00938889 | 0.489444
2916038 | 지상 2층 | 지상 2층 | 2914928 | 938.889 | 0.244722 | 0.00938889 | 0.489444
2916039 | 지상 2층 | 지상 2층 | 2914928 | 938.889 | 0.244722 | 0.00938889 | 0.489444
2916040 | 지상 2층 | 지상 2층 | 2914928 | 938.889 | 0.244722 | 0.00938889 | 0.489444
2916041 | 지상 2층 | 지상 2층 | 2914928 | 938.889 | 0.244722 | 0.00938889 | 0.489444
2916042 | 지상 2층 | 지상 2층 | 2914928 | 938.889 | 0.244722 | 0.00938889 | 0.489444
2916043 | 지상 2층 | 지상 2층 | 2914928 | 913.889 | 0.238472 | 0.00913889 | 0.476944
2916044 | 지상 2층 | 지상 2층 | 2914928 | 350 | 0.0975 | 0.0035 | 0.175
2916045 | 지상 2층 | 지상 2층 | 2914928 | 350 | 0.0975 | 0.0035 | 0.175
2916046 | 지상 2층 | 지상 2층 | 2914928 | 350 | 0.0975 | 0.0035 | 0.175
2916047 | 지상 2층 | 지상 2층 | 2914928 | 350 | 0.0975 | 0.0035 | 0.175
2916048 | 지상 2층 | 지상 2층 | 2914928 | 350 | 0.0975 | 0.0035 | 0.175
2916049 | 지상 2층 | 지상 2층 | 2914928 | 350 | 0.0975 | 0.0035 | 0.175
2916050 | 지상 2층 | 지상 2층 | 2914928 | 350 | 0.0975 | 0.0035 | 0.175
2916051 | 지상 2층 | 지상 2층 | 2914928 | 350 | 0.0975 | 0.0035 | 0.175
2917767 | 지상 3층 | 지상 3층 | 2917765 | 520 | 0.14 | 0.0052 | 0.28
2917768 | 지상 3층 | 지상 3층 | 2917765 | 525 | 0.14125 | 0.00525 | 0.2825
2917769 | 지상 3층 | 지상 3층 | 2917765 | 2100 | 0.535 | 0.021 | 1.06
2917770 | 지상 3층 | 지상 3층 | 2917765 | 520 | 0.14 | 0.0052 | 0.27
2917773 | 지상 3층 | 지상 3층 | 2917765 | 520 | 0.14 | 0.0052 | 0.27
2917774 | 지상 3층 | 지상 3층 | 2917765 | 2100 | 0.535 | 0.021 | 1.06
2917775 | 지상 3층 | 지상 3층 | 2917765 | 525 | 0.14125 | 0.00525 | 0.2825
2917779 | 지상 3층 | 지상 3층 | 2917765 | 525 | 0.14125 | 0.00525 | 0.2825
2917781 | 지상 3층 | 지상 3층 | 2917765 | 1505 | 0.38625 | 0.01505 | 0.7725
2917782 | 지상 3층 | 지상 3층 | 2917765 | 2100 | 0.535 | 0.021 | 1.06
2917783 | 지상 3층 | 지상 3층 | 2917765 | 520 | 0.14 | 0.0052 | 0.27
2917787 | 지상 3층 | 지상 3층 | 2917765 | 1505 | 0.38625 | 0.01505 | 0.7725
2917788 | 지상 3층 | 지상 3층 | 2917765 | 520 | 0.14 | 0.0052 | 0.28
2917789 | 지상 3층 | 지상 3층 | 2917765 | 520 | 0.14 | 0.0052 | 0.28
2917790 | 지상 3층 | 지상 3층 | 2917765 | 2100 | 0.535 | 0.021 | 1.06
2917791 | 지상 3층 | 지상 3층 | 2917765 | 520 | 0.14 | 0.0052 | 0.27
2918215 | 지상 2층 | 지상 2층 | 2918211 | 2635 | 0.66875 | 0.02635 | 1.3375
2918216 | 지상 2층 | 지상 2층 | 2918211 | 2265 | 0.57625 | 0.02265 | 1.1525
2918217 | 지상 2층 | 지상 2층 | 2918211 | 2100 | 0.535 | 0.021 | 1.06
2918218 | 지상 2층 | 지상 2층 | 2918211 | 920 | 0.24 | 0.0092 | 0.47
2918425 | 지상 2층 | 지상 2층 | 2918211 | 1500 | 0.385 | 0.015 | 0.77
2918426 | 지상 2층 | 지상 2층 | 2918211 | 2635 | 0.66875 | 0.02635 | 1.3375
2918427 | 지상 2층 | 지상 2층 | 2918211 | 2100 | 0.535 | 0.021 | 1.06
2918529 | 지상 2층 | 지상 2층 | 2918211 | 2265 | 0.57625 | 0.02265 | 1.1525
2918531 | 지상 2층 | 지상 2층 | 2918211 | 2100 | 0.535 | 0.021 | 1.06
2918630 | 지상 2층 | 지상 2층 | 2918211 | 920 | 0.24 | 0.0092 | 0.47
2918631 | 지상 2층 | 지상 2층 | 2918211 | 2100 | 0.535 | 0.021 | 1.06
2918632 | 지상 2층 | 지상 2층 | 2918211 | 2265 | 0.57625 | 0.02265 | 1.1525
2918633 | 지상 2층 | 지상 2층 | 2918211 | 1500 | 0.385 | 0.015 | 0.77
2918634 | 지상 2층 | 지상 2층 | 2918211 | 2635 | 0.66875 | 0.02635 | 1.3375
2918635 | 지상 2층 | 지상 2층 | 2918211 | 920 | 0.24 | 0.0092 | 0.47
2918636 | 지상 2층 | 지상 2층 | 2918211 | 920 | 0.24 | 0.0092 | 0.47
2918869 | 지상 3층 | 지상 3층 | 2918867 | 2635 | 0.66875 | 0.02635 | 1.3375
2918870 | 지상 3층 | 지상 3층 | 2918867 | 2265 | 0.57625 | 0.02265 | 1.1525
2918871 | 지상 3층 | 지상 3층 | 2918867 | 2100 | 0.535 | 0.021 | 1.06
2918872 | 지상 3층 | 지상 3층 | 2918867 | 520 | 0.14 | 0.0052 | 0.27
2918875 | 지상 3층 | 지상 3층 | 2918867 | 1500 | 0.385 | 0.015 | 0.77
2918876 | 지상 3층 | 지상 3층 | 2918867 | 2635 | 0.66875 | 0.02635 | 1.3375
2918877 | 지상 3층 | 지상 3층 | 2918867 | 2100 | 0.535 | 0.021 | 1.06
2918880 | 지상 3층 | 지상 3층 | 2918867 | 2265 | 0.57625 | 0.02265 | 1.1525
2918882 | 지상 3층 | 지상 3층 | 2918867 | 2100 | 0.535 | 0.021 | 1.06
2918887 | 지상 3층 | 지상 3층 | 2918867 | 520 | 0.14 | 0.0052 | 0.27
2918888 | 지상 3층 | 지상 3층 | 2918867 | 2100 | 0.535 | 0.021 | 1.06
2918889 | 지상 3층 | 지상 3층 | 2918867 | 2265 | 0.57625 | 0.02265 | 1.1525
2918890 | 지상 3층 | 지상 3층 | 2918867 | 1500 | 0.385 | 0.015 | 0.77
2918891 | 지상 3층 | 지상 3층 | 2918867 | 2635 | 0.66875 | 0.02635 | 1.3375
2918892 | 지상 3층 | 지상 3층 | 2918867 | 520 | 0.14 | 0.0052 | 0.27
2918893 | 지상 3층 | 지상 3층 | 2918867 | 520 | 0.14 | 0.0052 | 0.27
2919135 | 지상 10층 | 지상 10층 | 2919133 | 2685.03 | 0.681259 | 0.0268503 | 1.36252
2919137 | 지상 10층 | 지상 10층 | 2919133 | 2100 | 0.535 | 0.021 | 1.06
2919138 | 지상 10층 | 지상 10층 | 2919133 | 1420 | 0.365 | 0.0142 | 0.72
2919141 | 지상 10층 | 지상 10층 | 2919133 | 1500 | 0.385 | 0.015 | 0.77
2919143 | 지상 10층 | 지상 10층 | 2919133 | 2100 | 0.535 | 0.021 | 1.06
2919146 | 지상 10층 | 지상 10층 | 2919133 | 2314.97 | 0.588741 | 0.0231497 | 1.17748
2919148 | 지상 10층 | 지상 10층 | 2919133 | 2100 | 0.535 | 0.021 | 1.06
2919153 | 지상 10층 | 지상 10층 | 2919133 | 1420 | 0.365 | 0.0142 | 0.72
2919154 | 지상 10층 | 지상 10층 | 2919133 | 2100 | 0.535 | 0.021 | 1.06
2919155 | 지상 10층 | 지상 10층 | 2919133 | 2314.97 | 0.588741 | 0.0231497 | 1.17748
2919156 | 지상 10층 | 지상 10층 | 2919133 | 1500 | 0.385 | 0.015 | 0.77
2919157 | 지상 10층 | 지상 10층 | 2919133 | 2685.03 | 0.681259 | 0.0268503 | 1.36252
2919158 | 지상 10층 | 지상 10층 | 2919133 | 1420 | 0.365 | 0.0142 | 0.72
2919159 | 지상 10층 | 지상 10층 | 2919133 | 1420 | 0.365 | 0.0142 | 0.72
2919264 | 지상 2층 | 지상 2층 | 2919261 | 2534.97 | 0.643741 | 0.0253497 | 1.28748
2919265 | 지상 2층 | 지상 2층 | 2919261 | 2265 | 0.57625 | 0.02265 | 1.1525
2919266 | 지상 2층 | 지상 2층 | 2919261 | 2100 | 0.535 | 0.021 | 1.06
2919267 | 지상 2층 | 지상 2층 | 2919261 | 920 | 0.24 | 0.0092 | 0.47
2919562 | 지상 2층 | 지상 2층 | 2919261 | 1500 | 0.385 | 0.015 | 0.77
2919563 | 지상 2층 | 지상 2층 | 2919261 | 2534.97 | 0.643741 | 0.0253497 | 1.28748
2919564 | 지상 2층 | 지상 2층 | 2919261 | 2100 | 0.535 | 0.021 | 1.06
2919618 | 지상 2층 | 지상 2층 | 2919261 | 2265 | 0.57625 | 0.02265 | 1.1525
2919620 | 지상 2층 | 지상 2층 | 2919261 | 2100 | 0.535 | 0.021 | 1.06
2919693 | 지상 2층 | 지상 2층 | 2919261 | 920 | 0.24 | 0.0092 | 0.47
2919694 | 지상 2층 | 지상 2층 | 2919261 | 2100 | 0.535 | 0.021 | 1.06
2919695 | 지상 2층 | 지상 2층 | 2919261 | 2265 | 0.57625 | 0.02265 | 1.1525
2919696 | 지상 2층 | 지상 2층 | 2919261 | 1500 | 0.385 | 0.015 | 0.77
2919697 | 지상 2층 | 지상 2층 | 2919261 | 2534.97 | 0.643741 | 0.0253497 | 1.28748
2919698 | 지상 2층 | 지상 2층 | 2919261 | 920 | 0.24 | 0.0092 | 0.47
2919699 | 지상 2층 | 지상 2층 | 2919261 | 920 | 0.24 | 0.0092 | 0.47
2919871 | 지상 9층 | 지상 9층 | 2919869 | 2735.03 | 0.693759 | 0.0273503 | 1.38752
2919873 | 지상 9층 | 지상 9층 | 2919869 | 2100 | 0.535 | 0.021 | 1.06
2919874 | 지상 9층 | 지상 9층 | 2919869 | 920 | 0.24 | 0.0092 | 0.47
2919877 | 지상 9층 | 지상 9층 | 2919869 | 1500 | 0.385 | 0.015 | 0.77
2919879 | 지상 9층 | 지상 9층 | 2919869 | 2100 | 0.535 | 0.021 | 1.06
2919882 | 지상 9층 | 지상 9층 | 2919869 | 2365 | 0.60125 | 0.02365 | 1.2025
2919884 | 지상 9층 | 지상 9층 | 2919869 | 2100 | 0.535 | 0.021 | 1.06
2919889 | 지상 9층 | 지상 9층 | 2919869 | 920 | 0.24 | 0.0092 | 0.47
2919890 | 지상 9층 | 지상 9층 | 2919869 | 2100 | 0.535 | 0.021 | 1.06
2919891 | 지상 9층 | 지상 9층 | 2919869 | 2365 | 0.60125 | 0.02365 | 1.2025
2919892 | 지상 9층 | 지상 9층 | 2919869 | 1500 | 0.385 | 0.015 | 0.77
2919893 | 지상 9층 | 지상 9층 | 2919869 | 2735.03 | 0.693759 | 0.0273503 | 1.38752
2919894 | 지상 9층 | 지상 9층 | 2919869 | 920 | 0.24 | 0.0092 | 0.47
2919895 | 지상 9층 | 지상 9층 | 2919869 | 920 | 0.24 | 0.0092 | 0.47
2920061 | 지상 9층 | 지상 9층 | 2920059 | 2534.97 | 0.643741 | 0.0253497 | 1.28748
2920063 | 지상 9층 | 지상 9층 | 2920059 | 2100 | 0.535 | 0.021 | 1.06
2920064 | 지상 9층 | 지상 9층 | 2920059 | 920 | 0.24 | 0.0092 | 0.47
2920067 | 지상 9층 | 지상 9층 | 2920059 | 1500 | 0.385 | 0.015 | 0.77
2920069 | 지상 9층 | 지상 9층 | 2920059 | 2100 | 0.535 | 0.021 | 1.06
2920072 | 지상 9층 | 지상 9층 | 2920059 | 2265 | 0.57625 | 0.02265 | 1.1525
2920074 | 지상 9층 | 지상 9층 | 2920059 | 2100 | 0.535 | 0.021 | 1.06
2920079 | 지상 9층 | 지상 9층 | 2920059 | 920 | 0.24 | 0.0092 | 0.47
2920080 | 지상 9층 | 지상 9층 | 2920059 | 2100 | 0.535 | 0.021 | 1.06
2920081 | 지상 9층 | 지상 9층 | 2920059 | 2265 | 0.57625 | 0.02265 | 1.1525
2920082 | 지상 9층 | 지상 9층 | 2920059 | 1500 | 0.385 | 0.015 | 0.77
2920083 | 지상 9층 | 지상 9층 | 2920059 | 2534.97 | 0.643741 | 0.0253497 | 1.28748
2920084 | 지상 9층 | 지상 9층 | 2920059 | 920 | 0.24 | 0.0092 | 0.47
2920085 | 지상 9층 | 지상 9층 | 2920059 | 920 | 0.24 | 0.0092 | 0.47
2920395 | 지상 4층 | 지상 4층 | 2920393 | 2534.97 | 0.643741 | 0.0253497 | 1.28748
2920397 | 지상 4층 | 지상 4층 | 2920393 | 2100 | 0.535 | 0.021 | 1.06
2920398 | 지상 4층 | 지상 4층 | 2920393 | 520 | 0.14 | 0.0052 | 0.27
2920401 | 지상 4층 | 지상 4층 | 2920393 | 1500 | 0.385 | 0.015 | 0.77
2920403 | 지상 4층 | 지상 4층 | 2920393 | 2100 | 0.535 | 0.021 | 1.06
2920406 | 지상 4층 | 지상 4층 | 2920393 | 2265 | 0.57625 | 0.02265 | 1.1525
2920408 | 지상 4층 | 지상 4층 | 2920393 | 2100 | 0.535 | 0.021 | 1.06
2920413 | 지상 4층 | 지상 4층 | 2920393 | 520 | 0.14 | 0.0052 | 0.27
2920414 | 지상 4층 | 지상 4층 | 2920393 | 2100 | 0.535 | 0.021 | 1.06
2920415 | 지상 4층 | 지상 4층 | 2920393 | 2265 | 0.57625 | 0.02265 | 1.1525
2920416 | 지상 4층 | 지상 4층 | 2920393 | 1500 | 0.385 | 0.015 | 0.77
2920417 | 지상 4층 | 지상 4층 | 2920393 | 2534.97 | 0.643741 | 0.0253497 | 1.28748
2920418 | 지상 4층 | 지상 4층 | 2920393 | 520 | 0.14 | 0.0052 | 0.27
2920419 | 지상 4층 | 지상 4층 | 2920393 | 520 | 0.14 | 0.0052 | 0.27
2920540 | 지상 10층 | 지상 10층 | 2920538 | 2534.25 | 0.643563 | 0.0253425 | 1.28713
2920542 | 지상 10층 | 지상 10층 | 2920538 | 2100 | 0.535 | 0.021 | 1.06
2920543 | 지상 10층 | 지상 10층 | 2920538 | 1420 | 0.365 | 0.0142 | 0.72
2920546 | 지상 10층 | 지상 10층 | 2920538 | 1500 | 0.385 | 0.015 | 0.77
2920548 | 지상 10층 | 지상 10층 | 2920538 | 2100 | 0.535 | 0.021 | 1.06
2920551 | 지상 10층 | 지상 10층 | 2920538 | 2265 | 0.57625 | 0.02265 | 1.1525
2920553 | 지상 10층 | 지상 10층 | 2920538 | 2100 | 0.535 | 0.021 | 1.06
2920558 | 지상 10층 | 지상 10층 | 2920538 | 1420 | 0.365 | 0.0142 | 0.72
2920559 | 지상 10층 | 지상 10층 | 2920538 | 2100 | 0.535 | 0.021 | 1.06
2920560 | 지상 10층 | 지상 10층 | 2920538 | 2265 | 0.57625 | 0.02265 | 1.1525
2920561 | 지상 10층 | 지상 10층 | 2920538 | 1500 | 0.385 | 0.015 | 0.77
2920562 | 지상 10층 | 지상 10층 | 2920538 | 2534.25 | 0.643563 | 0.0253425 | 1.28713
2920563 | 지상 10층 | 지상 10층 | 2920538 | 1420 | 0.365 | 0.0142 | 0.72
2920564 | 지상 10층 | 지상 10층 | 2920538 | 1420 | 0.365 | 0.0142 | 0.72
2920613 | 지상 2층 | 지상 2층 | 2920611 | 423.145 | 0.115786 | 0.00423145 | 0.231573
2920614 | 지상 2층 | 지상 2층 | 2920611 | 376.829 | 0.104207 | 0.00376829 | 0.208415
2920615 | 지상 2층 | 지상 2층 | 2920611 | 2100 | 0.535 | 0.021 | 1.06
2920616 | 지상 2층 | 지상 2층 | 2920611 | 920 | 0.24 | 0.0092 | 0.47
2920619 | 지상 2층 | 지상 2층 | 2920611 | 920 | 0.24 | 0.0092 | 0.47
2920620 | 지상 2층 | 지상 2층 | 2920611 | 2100 | 0.535 | 0.021 | 1.06
2920621 | 지상 2층 | 지상 2층 | 2920611 | 376.847 | 0.104212 | 0.00376847 | 0.208423
2920625 | 지상 2층 | 지상 2층 | 2920611 | 376.847 | 0.104212 | 0.00376847 | 0.208423
2920627 | 지상 2층 | 지상 2층 | 2920611 | 1500 | 0.385 | 0.015 | 0.77
2920628 | 지상 2층 | 지상 2층 | 2920611 | 2100 | 0.535 | 0.021 | 1.06
2920629 | 지상 2층 | 지상 2층 | 2920611 | 920 | 0.24 | 0.0092 | 0.47
2920633 | 지상 2층 | 지상 2층 | 2920611 | 1500 | 0.385 | 0.015 | 0.77
2920634 | 지상 2층 | 지상 2층 | 2920611 | 423.145 | 0.115786 | 0.00423145 | 0.231573
2920635 | 지상 2층 | 지상 2층 | 2920611 | 423.145 | 0.115786 | 0.00423145 | 0.231573
2920636 | 지상 2층 | 지상 2층 | 2920611 | 2100 | 0.535 | 0.021 | 1.06
2920637 | 지상 2층 | 지상 2층 | 2920611 | 920 | 0.24 | 0.0092 | 0.47
2920737 | 지상 2층 | 지상 2층 | 2920734 | 2085 | 0.53125 | 0.02085 | 1.0625
2920738 | 지상 2층 | 지상 2층 | 2920734 | 1785 | 0.45625 | 0.01785 | 0.9125
2920739 | 지상 2층 | 지상 2층 | 2920734 | 2100 | 0.535 | 0.021 | 1.06
2920740 | 지상 2층 | 지상 2층 | 2920734 | 920 | 0.24 | 0.0092 | 0.47
2921147 | 지상 2층 | 지상 2층 | 2920734 | 920 | 0.24 | 0.0092 | 0.47
2921148 | 지상 2층 | 지상 2층 | 2920734 | 2100 | 0.535 | 0.021 | 1.06
2921149 | 지상 2층 | 지상 2층 | 2920734 | 1785 | 0.45625 | 0.01785 | 0.9125
2921201 | 지상 2층 | 지상 2층 | 2920734 | 1785 | 0.45625 | 0.01785 | 0.9125
2921202 | 지상 2층 | 지상 2층 | 2920734 | 1810 | 0.4625 | 0.0181 | 0.925
2921203 | 지상 2층 | 지상 2층 | 2920734 | 1810 | 0.4625 | 0.0181 | 0.925
2921204 | 지상 2층 | 지상 2층 | 2920734 | 2100 | 0.535 | 0.021 | 1.06
2921205 | 지상 2층 | 지상 2층 | 2920734 | 920 | 0.24 | 0.0092 | 0.47
2921281 | 지상 2층 | 지상 2층 | 2920734 | 1810 | 0.4625 | 0.0181 | 0.925
2921283 | 지상 2층 | 지상 2층 | 2920734 | 1500 | 0.385 | 0.015 | 0.77
2921284 | 지상 2층 | 지상 2층 | 2920734 | 2100 | 0.535 | 0.021 | 1.06
2921285 | 지상 2층 | 지상 2층 | 2920734 | 920 | 0.24 | 0.0092 | 0.47
2921339 | 지상 2층 | 지상 2층 | 2920734 | 1500 | 0.385 | 0.015 | 0.77
2921340 | 지상 2층 | 지상 2층 | 2920734 | 2420 | 0.615 | 0.0242 | 1.23
2921341 | 지상 2층 | 지상 2층 | 2920734 | 2420 | 0.615 | 0.0242 | 1.23
2921342 | 지상 2층 | 지상 2층 | 2920734 | 2100 | 0.535 | 0.021 | 1.06
2921343 | 지상 2층 | 지상 2층 | 2920734 | 920 | 0.24 | 0.0092 | 0.47
2921445 | 지상 2층 | 지상 2층 | 2920734 | 2420 | 0.615 | 0.0242 | 1.23
2921446 | 지상 2층 | 지상 2층 | 2920734 | 2085 | 0.53125 | 0.02085 | 1.0625
2921447 | 지상 2층 | 지상 2층 | 2920734 | 2085 | 0.53125 | 0.02085 | 1.0625
2921448 | 지상 2층 | 지상 2층 | 2920734 | 2100 | 0.535 | 0.021 | 1.06
2921449 | 지상 2층 | 지상 2층 | 2920734 | 920 | 0.24 | 0.0092 | 0.47
2921991 | 지상 3층 | 지상 3층 | 2921989 | 423.145 | 0.115786 | 0.00423145 | 0.231573
2921993 | 지상 3층 | 지상 3층 | 2921989 | 2100 | 0.535 | 0.021 | 1.06
2921994 | 지상 3층 | 지상 3층 | 2921989 | 520 | 0.14 | 0.0052 | 0.27
2921997 | 지상 3층 | 지상 3층 | 2921989 | 520 | 0.14 | 0.0052 | 0.27
2921998 | 지상 3층 | 지상 3층 | 2921989 | 2100 | 0.535 | 0.021 | 1.06
2921999 | 지상 3층 | 지상 3층 | 2921989 | 376.847 | 0.104212 | 0.00376847 | 0.208423
2922003 | 지상 3층 | 지상 3층 | 2921989 | 376.847 | 0.104212 | 0.00376847 | 0.208423
2922005 | 지상 3층 | 지상 3층 | 2921989 | 1500 | 0.385 | 0.015 | 0.77
2922006 | 지상 3층 | 지상 3층 | 2921989 | 2100 | 0.535 | 0.021 | 1.06
2922007 | 지상 3층 | 지상 3층 | 2921989 | 520 | 0.14 | 0.0052 | 0.27
2922011 | 지상 3층 | 지상 3층 | 2921989 | 1500 | 0.385 | 0.015 | 0.77
2922013 | 지상 3층 | 지상 3층 | 2921989 | 423.145 | 0.115786 | 0.00423145 | 0.231573
2922014 | 지상 3층 | 지상 3층 | 2921989 | 2100 | 0.535 | 0.021 | 1.06
2922015 | 지상 3층 | 지상 3층 | 2921989 | 520 | 0.14 | 0.0052 | 0.27
2922165 | 지상 9층 | 지상 9층 | 2922163 | 425 | 0.11625 | 0.00425 | 0.2325
2922167 | 지상 9층 | 지상 9층 | 2922163 | 2100 | 0.535 | 0.021 | 1.06
2922168 | 지상 9층 | 지상 9층 | 2922163 | 920 | 0.24 | 0.0092 | 0.47
2922171 | 지상 9층 | 지상 9층 | 2922163 | 920 | 0.24 | 0.0092 | 0.47
2922172 | 지상 9층 | 지상 9층 | 2922163 | 2100 | 0.535 | 0.021 | 1.06
2922173 | 지상 9층 | 지상 9층 | 2922163 | 375 | 0.10375 | 0.00375 | 0.2075
2922177 | 지상 9층 | 지상 9층 | 2922163 | 375 | 0.10375 | 0.00375 | 0.2075
2922179 | 지상 9층 | 지상 9층 | 2922163 | 1500 | 0.385 | 0.015 | 0.77
2922180 | 지상 9층 | 지상 9층 | 2922163 | 2100 | 0.535 | 0.021 | 1.06
2922181 | 지상 9층 | 지상 9층 | 2922163 | 920 | 0.24 | 0.0092 | 0.47
2922185 | 지상 9층 | 지상 9층 | 2922163 | 1500 | 0.385 | 0.015 | 0.77
2922187 | 지상 9층 | 지상 9층 | 2922163 | 425 | 0.11625 | 0.00425 | 0.2325
2922188 | 지상 9층 | 지상 9층 | 2922163 | 2100 | 0.535 | 0.021 | 1.06
2922189 | 지상 9층 | 지상 9층 | 2922163 | 920 | 0.24 | 0.0092 | 0.47
2922194 | 지상 10층 | 지상 10층 | 2922192 | 425 | 0.11625 | 0.00425 | 0.2325
2922196 | 지상 10층 | 지상 10층 | 2922192 | 2100 | 0.535 | 0.021 | 1.06
2922197 | 지상 10층 | 지상 10층 | 2922192 | 1420 | 0.365 | 0.0142 | 0.72
2922200 | 지상 10층 | 지상 10층 | 2922192 | 1420 | 0.365 | 0.0142 | 0.72
2922201 | 지상 10층 | 지상 10층 | 2922192 | 2100 | 0.535 | 0.021 | 1.06
2922202 | 지상 10층 | 지상 10층 | 2922192 | 375 | 0.10375 | 0.00375 | 0.2075
2922206 | 지상 10층 | 지상 10층 | 2922192 | 375 | 0.10375 | 0.00375 | 0.2075
2922208 | 지상 10층 | 지상 10층 | 2922192 | 1500 | 0.385 | 0.015 | 0.77
2922209 | 지상 10층 | 지상 10층 | 2922192 | 2100 | 0.535 | 0.021 | 1.06
2922210 | 지상 10층 | 지상 10층 | 2922192 | 1420 | 0.365 | 0.0142 | 0.72
2922214 | 지상 10층 | 지상 10층 | 2922192 | 1500 | 0.385 | 0.015 | 0.77
2922216 | 지상 10층 | 지상 10층 | 2922192 | 425 | 0.11625 | 0.00425 | 0.2325
2922217 | 지상 10층 | 지상 10층 | 2922192 | 2100 | 0.535 | 0.021 | 1.06
2922218 | 지상 10층 | 지상 10층 | 2922192 | 1420 | 0.365 | 0.0142 | 0.72
2923037 | 지상 3층 | 지상 3층 | 2923035 | 2085 | 0.53125 | 0.02085 | 1.0625
2923039 | 지상 3층 | 지상 3층 | 2923035 | 2100 | 0.535 | 0.021 | 1.06
2923040 | 지상 3층 | 지상 3층 | 2923035 | 520 | 0.14 | 0.0052 | 0.27
2923043 | 지상 3층 | 지상 3층 | 2923035 | 520 | 0.14 | 0.0052 | 0.27
2923044 | 지상 3층 | 지상 3층 | 2923035 | 2100 | 0.535 | 0.021 | 1.06
2923045 | 지상 3층 | 지상 3층 | 2923035 | 1785 | 0.45625 | 0.01785 | 0.9125
2923049 | 지상 3층 | 지상 3층 | 2923035 | 1785 | 0.45625 | 0.01785 | 0.9125
2923051 | 지상 3층 | 지상 3층 | 2923035 | 1810 | 0.4625 | 0.0181 | 0.925
2923052 | 지상 3층 | 지상 3층 | 2923035 | 2100 | 0.535 | 0.021 | 1.06
2923053 | 지상 3층 | 지상 3층 | 2923035 | 520 | 0.14 | 0.0052 | 0.27
2923057 | 지상 3층 | 지상 3층 | 2923035 | 1810 | 0.4625 | 0.0181 | 0.925
2923059 | 지상 3층 | 지상 3층 | 2923035 | 1810 | 0.4625 | 0.0181 | 0.925
2923060 | 지상 3층 | 지상 3층 | 2923035 | 2100 | 0.535 | 0.021 | 1.06
2923061 | 지상 3층 | 지상 3층 | 2923035 | 520 | 0.14 | 0.0052 | 0.27
2923065 | 지상 3층 | 지상 3층 | 2923035 | 1810 | 0.4625 | 0.0181 | 0.925
2923067 | 지상 3층 | 지상 3층 | 2923035 | 2110 | 0.5375 | 0.0211 | 1.075
2923068 | 지상 3층 | 지상 3층 | 2923035 | 2100 | 0.535 | 0.021 | 1.06
2923069 | 지상 3층 | 지상 3층 | 2923035 | 520 | 0.14 | 0.0052 | 0.27
2923073 | 지상 3층 | 지상 3층 | 2923035 | 2110 | 0.5375 | 0.0211 | 1.075
2923075 | 지상 3층 | 지상 3층 | 2923035 | 2085 | 0.53125 | 0.02085 | 1.0625
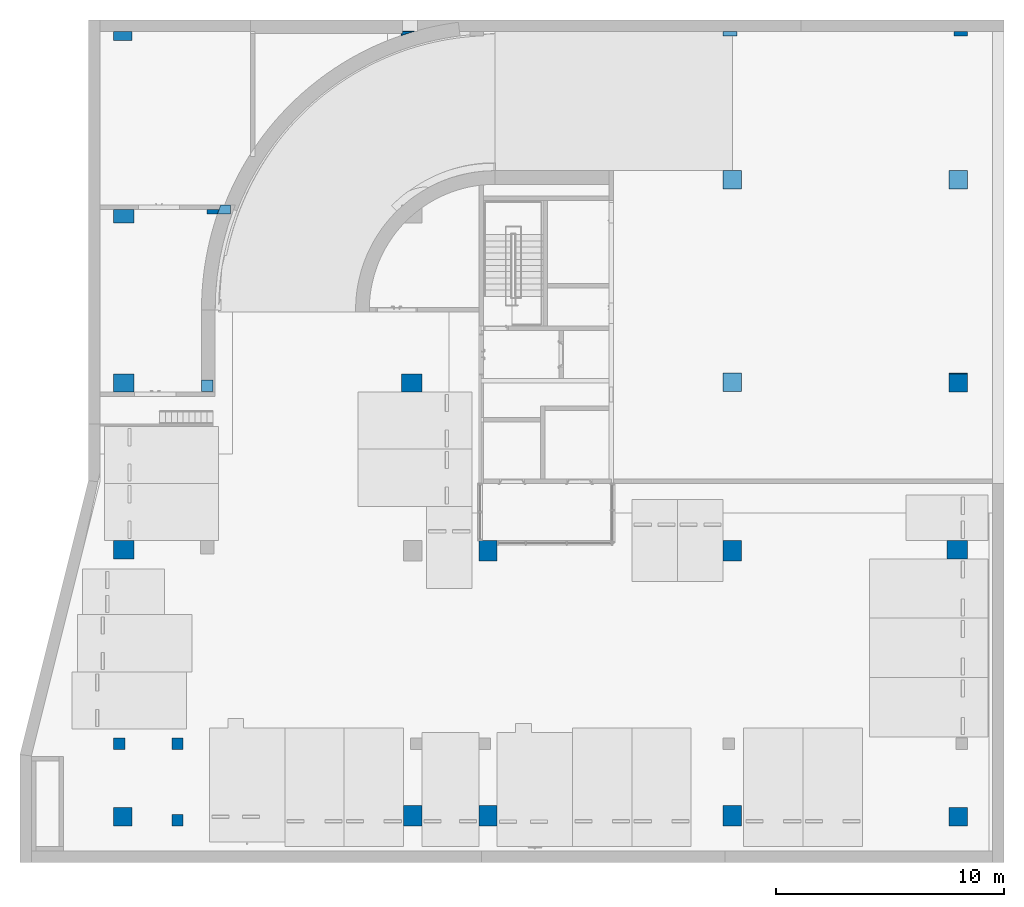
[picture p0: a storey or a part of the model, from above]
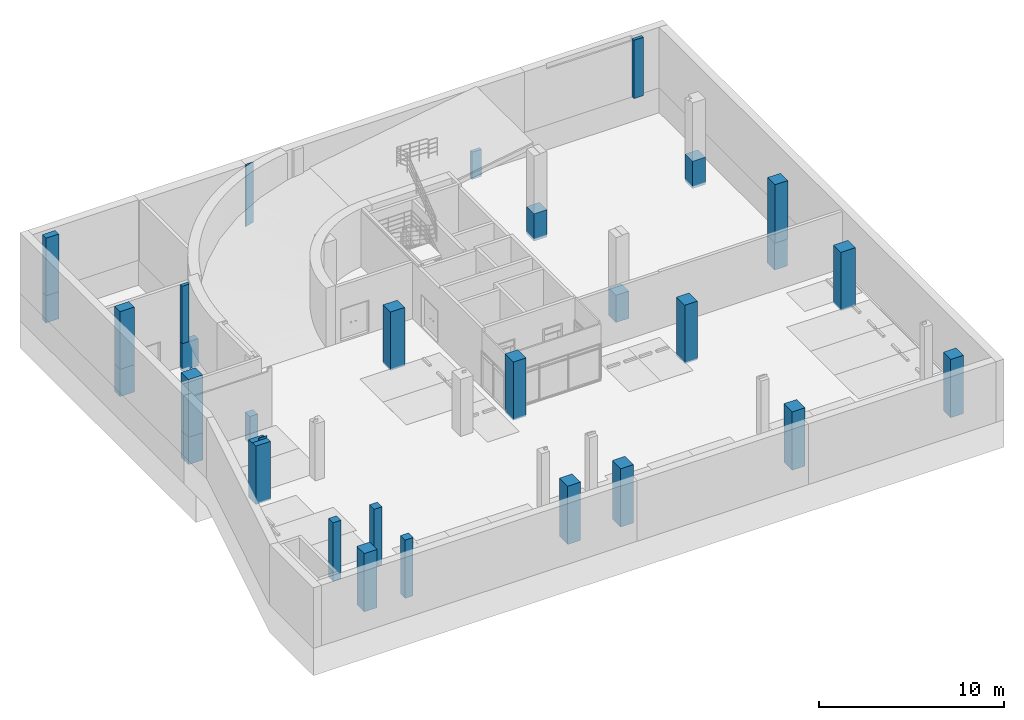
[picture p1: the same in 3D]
Properties of the parts of a building model (IFC2X3), part 16 of 39

# IfcMember: 직사각형 멀리언:CW200-직사각형 멀리언 50x200mm (8700)
Name (직사각형 멀리언:CW200-직사각형 멀리언 50x200mm:...) | In | 레벨 | 호스트 ID | 길이 (mm) = Span (mm) | 면적 (m2) = CrossSectionArea (m2) | 체적 (m3) = NetVolume (m3) | NetSurfaceArea (m2)
2923076 | 지상 3층 | 지상 3층 | 2923035 | 2100 | 0.535 | 0.021 | 1.06
2923077 | 지상 3층 | 지상 3층 | 2923035 | 520 | 0.14 | 0.0052 | 0.27
2923307 | 지상 9층 | 지상 9층 | 2923305 | 2085 | 0.53125 | 0.02085 | 1.0625
2923309 | 지상 9층 | 지상 9층 | 2923305 | 2100 | 0.535 | 0.021 | 1.06
2923310 | 지상 9층 | 지상 9층 | 2923305 | 920 | 0.24 | 0.0092 | 0.47
2923313 | 지상 9층 | 지상 9층 | 2923305 | 920 | 0.24 | 0.0092 | 0.47
2923314 | 지상 9층 | 지상 9층 | 2923305 | 2100 | 0.535 | 0.021 | 1.06
2923315 | 지상 9층 | 지상 9층 | 2923305 | 1885 | 0.48125 | 0.01885 | 0.9625
2923319 | 지상 9층 | 지상 9층 | 2923305 | 1885 | 0.48125 | 0.01885 | 0.9625
2923321 | 지상 9층 | 지상 9층 | 2923305 | 1810 | 0.4625 | 0.0181 | 0.925
2923322 | 지상 9층 | 지상 9층 | 2923305 | 2100 | 0.535 | 0.021 | 1.06
2923323 | 지상 9층 | 지상 9층 | 2923305 | 920 | 0.24 | 0.0092 | 0.47
2923327 | 지상 9층 | 지상 9층 | 2923305 | 1810 | 0.4625 | 0.0181 | 0.925
2923329 | 지상 9층 | 지상 9층 | 2923305 | 1500 | 0.385 | 0.015 | 0.77
2923330 | 지상 9층 | 지상 9층 | 2923305 | 2100 | 0.535 | 0.021 | 1.06
2923331 | 지상 9층 | 지상 9층 | 2923305 | 920 | 0.24 | 0.0092 | 0.47
2923335 | 지상 9층 | 지상 9층 | 2923305 | 1500 | 0.385 | 0.015 | 0.77
2923337 | 지상 9층 | 지상 9층 | 2923305 | 2420 | 0.615 | 0.0242 | 1.23
2923338 | 지상 9층 | 지상 9층 | 2923305 | 2100 | 0.535 | 0.021 | 1.06
2923339 | 지상 9층 | 지상 9층 | 2923305 | 920 | 0.24 | 0.0092 | 0.47
2923343 | 지상 9층 | 지상 9층 | 2923305 | 2420 | 0.615 | 0.0242 | 1.23
2923345 | 지상 9층 | 지상 9층 | 2923305 | 2085 | 0.53125 | 0.02085 | 1.0625
2923346 | 지상 9층 | 지상 9층 | 2923305 | 2100 | 0.535 | 0.021 | 1.06
2923347 | 지상 9층 | 지상 9층 | 2923305 | 920 | 0.24 | 0.0092 | 0.47
2923352 | 지상 10층 | 지상 10층 | 2923350 | 2085 | 0.53125 | 0.02085 | 1.0625
2923354 | 지상 10층 | 지상 10층 | 2923350 | 2100 | 0.535 | 0.021 | 1.06
2923355 | 지상 10층 | 지상 10층 | 2923350 | 1420 | 0.365 | 0.0142 | 0.72
2923358 | 지상 10층 | 지상 10층 | 2923350 | 1420 | 0.365 | 0.0142 | 0.72
2923359 | 지상 10층 | 지상 10층 | 2923350 | 2100 | 0.535 | 0.021 | 1.06
2923360 | 지상 10층 | 지상 10층 | 2923350 | 1885 | 0.48125 | 0.01885 | 0.9625
2923364 | 지상 10층 | 지상 10층 | 2923350 | 1885 | 0.48125 | 0.01885 | 0.9625
2923366 | 지상 10층 | 지상 10층 | 2923350 | 1810 | 0.4625 | 0.0181 | 0.925
2923367 | 지상 10층 | 지상 10층 | 2923350 | 2100 | 0.535 | 0.021 | 1.06
2923368 | 지상 10층 | 지상 10층 | 2923350 | 1420 | 0.365 | 0.0142 | 0.72
2923372 | 지상 10층 | 지상 10층 | 2923350 | 1810 | 0.4625 | 0.0181 | 0.925
2923374 | 지상 10층 | 지상 10층 | 2923350 | 1500 | 0.385 | 0.015 | 0.77
2923375 | 지상 10층 | 지상 10층 | 2923350 | 2100 | 0.535 | 0.021 | 1.06
2923376 | 지상 10층 | 지상 10층 | 2923350 | 1420 | 0.365 | 0.0142 | 0.72
2923380 | 지상 10층 | 지상 10층 | 2923350 | 1500 | 0.385 | 0.015 | 0.77
2923382 | 지상 10층 | 지상 10층 | 2923350 | 2420 | 0.615 | 0.0242 | 1.23
2923383 | 지상 10층 | 지상 10층 | 2923350 | 2100 | 0.535 | 0.021 | 1.06
2923384 | 지상 10층 | 지상 10층 | 2923350 | 1420 | 0.365 | 0.0142 | 0.72
2923388 | 지상 10층 | 지상 10층 | 2923350 | 2420 | 0.615 | 0.0242 | 1.23
2923390 | 지상 10층 | 지상 10층 | 2923350 | 2085 | 0.53125 | 0.02085 | 1.0625
2923391 | 지상 10층 | 지상 10층 | 2923350 | 2100 | 0.535 | 0.021 | 1.06
2923392 | 지상 10층 | 지상 10층 | 2923350 | 1420 | 0.365 | 0.0142 | 0.72
2923465 | 지상 2층 | 지상 2층 | 2923462 | 2068 | 0.527 | 0.02068 | 1.054
2923466 | 지상 2층 | 지상 2층 | 2923462 | 2068 | 0.527 | 0.02068 | 1.054
2923468 | 지상 2층 | 지상 2층 | 2923462 | 920 | 0.24 | 0.0092 | 0.47
2924247 | 지상 2층 | 지상 2층 | 2923462 | 2100 | 0.535 | 0.021 | 1.06
2924248 | 지상 2층 | 지상 2층 | 2923462 | 2068 | 0.527 | 0.02068 | 1.054
2923552 | 지상 2층 | 지상 2층 | 2923549 | 458 | 0.1245 | 0.00458 | 0.249
2923553 | 지상 2층 | 지상 2층 | 2923549 | 462.983 | 0.125746 | 0.00462983 | 0.251491
2924405 | 지상 2층 | 지상 2층 | 2923549 | 462.983 | 0.125746 | 0.00462983 | 0.251491
2924407 | 지상 2층 | 지상 2층 | 2923549 | 2100 | 0.535 | 0.021 | 1.06
2924472 | 지상 2층 | 지상 2층 | 2923549 | 462.983 | 0.125746 | 0.00462983 | 0.251491
2924473 | 지상 2층 | 지상 2층 | 2923549 | 1500 | 0.385 | 0.015 | 0.77
2924474 | 지상 2층 | 지상 2층 | 2923549 | 920 | 0.24 | 0.0092 | 0.47
2924633 | 지상 2층 | 지상 2층 | 2923549 | 1500 | 0.385 | 0.015 | 0.77
2924634 | 지상 2층 | 지상 2층 | 2923549 | 458 | 0.1245 | 0.00458 | 0.249
2924635 | 지상 2층 | 지상 2층 | 2923549 | 458 | 0.1245 | 0.00458 | 0.249
2924636 | 지상 2층 | 지상 2층 | 2923549 | 2100 | 0.535 | 0.021 | 1.06
2924637 | 지상 2층 | 지상 2층 | 2923549 | 920 | 0.24 | 0.0092 | 0.47
2923618 | 지상 2층 | 지상 2층 | 2923615 | 280.009 | 0.0800022 | 0.00280009 | 0.160004
2923619 | 지상 2층 | 지상 2층 | 2923615 | 783 | 0.20575 | 0.00783 | 0.4115
2923620 | 지상 2층 | 지상 2층 | 2923615 | 2100 | 0.535 | 0.021 | 1.06
2924902 | 지상 2층 | 지상 2층 | 2923615 | 920 | 0.24 | 0.0092 | 0.47
2924904 | 지상 2층 | 지상 2층 | 2923615 | 783 | 0.20575 | 0.00783 | 0.4115
2925058 | 지상 2층 | 지상 2층 | 2923615 | 783 | 0.20575 | 0.00783 | 0.4115
2925060 | 지상 2층 | 지상 2층 | 2923615 | 1495 | 0.38375 | 0.01495 | 0.7675
2925061 | 지상 2층 | 지상 2층 | 2923615 | 2100 | 0.535 | 0.021 | 1.06
2925062 | 지상 2층 | 지상 2층 | 2923615 | 920 | 0.24 | 0.0092 | 0.47
7694606 | 지상 2층 | 지상 2층 | 2923615 | 1495 | 0.38375 | 0.01495 | 0.7675
7694607 | 지상 2층 | 지상 2층 | 2923615 | 280.009 | 0.0800022 | 0.00280009 | 0.160004
2926333 | 지상 3층 | 지상 3층 | 2926331 | 1124.68 | 0.291171 | 0.0112468 | 0.582342
2926334 | 지상 3층 | 지상 3층 | 2926331 | 874.684 | 0.228671 | 0.00874684 | 0.457342
2926335 | 지상 3층 | 지상 3층 | 2926331 | 900 | 0.235 | 0.009 | 0.46
2926339 | 지상 3층 | 지상 3층 | 2926331 | 1220 | 0.315 | 0.0122 | 0.62
2926341 | 지상 3층 | 지상 3층 | 2926331 | 874.684 | 0.228671 | 0.00874684 | 0.457342
2926344 | 지상 3층 | 지상 3층 | 2926331 | 500 | 0.135 | 0.005 | 0.25
2926346 | 지상 3층 | 지상 3층 | 2926331 | 874.684 | 0.228671 | 0.00874684 | 0.457342
2926482 | 지상 3층 | 지상 3층 | 2926331 | 874.684 | 0.228671 | 0.00874684 | 0.457342
2926483 | 지상 3층 | 지상 3층 | 2926331 | 1124.68 | 0.291171 | 0.0112468 | 0.582342
2926484 | 지상 3층 | 지상 3층 | 2926331 | 1124.68 | 0.291171 | 0.0112468 | 0.582342
2926485 | 지상 3층 | 지상 3층 | 2926331 | 1124.68 | 0.291171 | 0.0112468 | 0.582342
2926486 | 지상 3층 | 지상 3층 | 2926331 | 900 | 0.235 | 0.009 | 0.46
2926487 | 지상 3층 | 지상 3층 | 2926331 | 500 | 0.135 | 0.005 | 0.25
2926488 | 지상 3층 | 지상 3층 | 2926331 | 1220 | 0.315 | 0.0122 | 0.62
2927267 | 지상 3층 | 지상 3층 | 2927264 | 912.5 | 0.238125 | 0.009125 | 0.47625
2927268 | 지상 3층 | 지상 3층 | 2927264 | 778.655 | 0.204664 | 0.00778655 | 0.409328
2929189 | 지상 3층 | 지상 3층 | 2927264 | 778.655 | 0.204664 | 0.00778655 | 0.409328
2929444 | 지상 3층 | 지상 3층 | 2927264 | 778.655 | 0.204664 | 0.00778655 | 0.409328
2929655 | 지상 3층 | 지상 3층 | 2927264 | 778.655 | 0.204664 | 0.00778655 | 0.409328
2929656 | 지상 3층 | 지상 3층 | 2927264 | 894 | 0.2335 | 0.00894 | 0.467
2929657 | 지상 3층 | 지상 3층 | 2927264 | 894 | 0.2335 | 0.00894 | 0.467
2929658 | 지상 3층 | 지상 3층 | 2927264 | 894 | 0.2335 | 0.00894 | 0.467
2929659 | 지상 3층 | 지상 3층 | 2927264 | 950 | 0.2475 | 0.0095 | 0.485
2929660 | 지상 3층 | 지상 3층 | 2927264 | 600 | 0.16 | 0.006 | 0.3
2929661 | 지상 3층 | 지상 3층 | 2927264 | 1070 | 0.2775 | 0.0107 | 0.545
2929798 | 지상 3층 | 지상 3층 | 2927264 | 894 | 0.2335 | 0.00894 | 0.467
2929799 | 지상 3층 | 지상 3층 | 2927264 | 804 | 0.211 | 0.00804 | 0.422
2929800 | 지상 3층 | 지상 3층 | 2927264 | 804 | 0.211 | 0.00804 | 0.422
2929801 | 지상 3층 | 지상 3층 | 2927264 | 804 | 0.211 | 0.00804 | 0.422
2929802 | 지상 3층 | 지상 3층 | 2927264 | 950 | 0.2475 | 0.0095 | 0.485
2929803 | 지상 3층 | 지상 3층 | 2927264 | 600 | 0.16 | 0.006 | 0.3
2929804 | 지상 3층 | 지상 3층 | 2927264 | 1070 | 0.2775 | 0.0107 | 0.545
2930107 | 지상 3층 | 지상 3층 | 2927264 | 804 | 0.211 | 0.00804 | 0.422
2930152 | 지상 3층 | 지상 3층 | 2927264 | 950 | 0.2475 | 0.0095 | 0.485
2930153 | 지상 3층 | 지상 3층 | 2927264 | 600 | 0.16 | 0.006 | 0.3
2930154 | 지상 3층 | 지상 3층 | 2927264 | 1070 | 0.2775 | 0.0107 | 0.545
2930240 | 지상 3층 | 지상 3층 | 2927264 | 950 | 0.2475 | 0.0095 | 0.485
2930241 | 지상 3층 | 지상 3층 | 2927264 | 600 | 0.16 | 0.006 | 0.3
2930242 | 지상 3층 | 지상 3층 | 2927264 | 1070 | 0.2775 | 0.0107 | 0.545
2930324 | 지상 3층 | 지상 3층 | 2927264 | 804 | 0.211 | 0.00804 | 0.422
2930325 | 지상 3층 | 지상 3층 | 2927264 | 804 | 0.211 | 0.00804 | 0.422
2930326 | 지상 3층 | 지상 3층 | 2927264 | 804 | 0.211 | 0.00804 | 0.422
2930327 | 지상 3층 | 지상 3층 | 2927264 | 804 | 0.211 | 0.00804 | 0.422
2930328 | 지상 3층 | 지상 3층 | 2927264 | 950 | 0.2475 | 0.0095 | 0.485
2930329 | 지상 3층 | 지상 3층 | 2927264 | 600 | 0.16 | 0.006 | 0.3
2930330 | 지상 3층 | 지상 3층 | 2927264 | 1070 | 0.2775 | 0.0107 | 0.545
2930406 | 지상 3층 | 지상 3층 | 2927264 | 804 | 0.211 | 0.00804 | 0.422
2930407 | 지상 3층 | 지상 3층 | 2927264 | 804 | 0.211 | 0.00804 | 0.422
2930408 | 지상 3층 | 지상 3층 | 2927264 | 804 | 0.211 | 0.00804 | 0.422
2930409 | 지상 3층 | 지상 3층 | 2927264 | 804 | 0.211 | 0.00804 | 0.422
2930410 | 지상 3층 | 지상 3층 | 2927264 | 950 | 0.2475 | 0.0095 | 0.485
2930411 | 지상 3층 | 지상 3층 | 2927264 | 600 | 0.16 | 0.006 | 0.3
2930412 | 지상 3층 | 지상 3층 | 2927264 | 1070 | 0.2775 | 0.0107 | 0.545
2930488 | 지상 3층 | 지상 3층 | 2927264 | 804 | 0.211 | 0.00804 | 0.422
2930489 | 지상 3층 | 지상 3층 | 2927264 | 804 | 0.211 | 0.00804 | 0.422
2930490 | 지상 3층 | 지상 3층 | 2927264 | 804 | 0.211 | 0.00804 | 0.422
2930491 | 지상 3층 | 지상 3층 | 2927264 | 804 | 0.211 | 0.00804 | 0.422
2930492 | 지상 3층 | 지상 3층 | 2927264 | 950 | 0.2475 | 0.0095 | 0.485
2930493 | 지상 3층 | 지상 3층 | 2927264 | 600 | 0.16 | 0.006 | 0.3
2930494 | 지상 3층 | 지상 3층 | 2927264 | 1070 | 0.2775 | 0.0107 | 0.545
2930532 | 지상 3층 | 지상 3층 | 2927264 | 804 | 0.211 | 0.00804 | 0.422
2930533 | 지상 3층 | 지상 3층 | 2927264 | 864 | 0.226 | 0.00864 | 0.452
2930534 | 지상 3층 | 지상 3층 | 2927264 | 864 | 0.226 | 0.00864 | 0.452
2930535 | 지상 3층 | 지상 3층 | 2927264 | 864 | 0.226 | 0.00864 | 0.452
2930536 | 지상 3층 | 지상 3층 | 2927264 | 950 | 0.2475 | 0.0095 | 0.485
2930537 | 지상 3층 | 지상 3층 | 2927264 | 600 | 0.16 | 0.006 | 0.3
2930538 | 지상 3층 | 지상 3층 | 2927264 | 1070 | 0.2775 | 0.0107 | 0.545
2930570 | 지상 3층 | 지상 3층 | 2927264 | 864 | 0.226 | 0.00864 | 0.452
2930571 | 지상 3층 | 지상 3층 | 2927264 | 1000 | 0.26 | 0.01 | 0.52
2930572 | 지상 3층 | 지상 3층 | 2927264 | 1000 | 0.26 | 0.01 | 0.52
2930573 | 지상 3층 | 지상 3층 | 2927264 | 1000 | 0.26 | 0.01 | 0.52
2930574 | 지상 3층 | 지상 3층 | 2927264 | 950 | 0.2475 | 0.0095 | 0.485
2930575 | 지상 3층 | 지상 3층 | 2927264 | 600 | 0.16 | 0.006 | 0.3
2930576 | 지상 3층 | 지상 3층 | 2927264 | 1070 | 0.2775 | 0.0107 | 0.545
2930646 | 지상 3층 | 지상 3층 | 2927264 | 1000 | 0.26 | 0.01 | 0.52
2930647 | 지상 3층 | 지상 3층 | 2927264 | 789 | 0.20725 | 0.00789 | 0.4145
2930648 | 지상 3층 | 지상 3층 | 2927264 | 789 | 0.20725 | 0.00789 | 0.4145
2930649 | 지상 3층 | 지상 3층 | 2927264 | 789 | 0.20725 | 0.00789 | 0.4145
2930650 | 지상 3층 | 지상 3층 | 2927264 | 950 | 0.2475 | 0.0095 | 0.485
2930651 | 지상 3층 | 지상 3층 | 2927264 | 600 | 0.16 | 0.006 | 0.3
2930652 | 지상 3층 | 지상 3층 | 2927264 | 1070 | 0.2775 | 0.0107 | 0.545
2930684 | 지상 3층 | 지상 3층 | 2927264 | 789 | 0.20725 | 0.00789 | 0.4145
2930685 | 지상 3층 | 지상 3층 | 2927264 | 729 | 0.19225 | 0.00729 | 0.3845
2930686 | 지상 3층 | 지상 3층 | 2927264 | 729 | 0.19225 | 0.00729 | 0.3845
2930687 | 지상 3층 | 지상 3층 | 2927264 | 729 | 0.19225 | 0.00729 | 0.3845
2930688 | 지상 3층 | 지상 3층 | 2927264 | 950 | 0.2475 | 0.0095 | 0.485
2930689 | 지상 3층 | 지상 3층 | 2927264 | 600 | 0.16 | 0.006 | 0.3
2930690 | 지상 3층 | 지상 3층 | 2927264 | 1070 | 0.2775 | 0.0107 | 0.545
2930722 | 지상 3층 | 지상 3층 | 2927264 | 729 | 0.19225 | 0.00729 | 0.3845
2930723 | 지상 3층 | 지상 3층 | 2927264 | 729 | 0.19225 | 0.00729 | 0.3845
2930724 | 지상 3층 | 지상 3층 | 2927264 | 729 | 0.19225 | 0.00729 | 0.3845
2930725 | 지상 3층 | 지상 3층 | 2927264 | 729 | 0.19225 | 0.00729 | 0.3845
2930726 | 지상 3층 | 지상 3층 | 2927264 | 950 | 0.2475 | 0.0095 | 0.485
2930727 | 지상 3층 | 지상 3층 | 2927264 | 600 | 0.16 | 0.006 | 0.3
2930728 | 지상 3층 | 지상 3층 | 2927264 | 1070 | 0.2775 | 0.0107 | 0.545
2930804 | 지상 3층 | 지상 3층 | 2927264 | 729 | 0.19225 | 0.00729 | 0.3845
2930805 | 지상 3층 | 지상 3층 | 2927264 | 729 | 0.19225 | 0.00729 | 0.3845
2930806 | 지상 3층 | 지상 3층 | 2927264 | 729 | 0.19225 | 0.00729 | 0.3845
2930807 | 지상 3층 | 지상 3층 | 2927264 | 729 | 0.19225 | 0.00729 | 0.3845
2930808 | 지상 3층 | 지상 3층 | 2927264 | 950 | 0.2475 | 0.0095 | 0.485
2930809 | 지상 3층 | 지상 3층 | 2927264 | 600 | 0.16 | 0.006 | 0.3
2930810 | 지상 3층 | 지상 3층 | 2927264 | 1070 | 0.2775 | 0.0107 | 0.545
2930842 | 지상 3층 | 지상 3층 | 2927264 | 729 | 0.19225 | 0.00729 | 0.3845
2930843 | 지상 3층 | 지상 3층 | 2927264 | 729 | 0.19225 | 0.00729 | 0.3845
2930844 | 지상 3층 | 지상 3층 | 2927264 | 729 | 0.19225 | 0.00729 | 0.3845
2930845 | 지상 3층 | 지상 3층 | 2927264 | 729 | 0.19225 | 0.00729 | 0.3845
2930846 | 지상 3층 | 지상 3층 | 2927264 | 950 | 0.2475 | 0.0095 | 0.485
2930847 | 지상 3층 | 지상 3층 | 2927264 | 600 | 0.16 | 0.006 | 0.3
2930848 | 지상 3층 | 지상 3층 | 2927264 | 1070 | 0.2775 | 0.0107 | 0.545
2930880 | 지상 3층 | 지상 3층 | 2927264 | 729 | 0.19225 | 0.00729 | 0.3845
2930881 | 지상 3층 | 지상 3층 | 2927264 | 729 | 0.19225 | 0.00729 | 0.3845
2930882 | 지상 3층 | 지상 3층 | 2927264 | 729 | 0.19225 | 0.00729 | 0.3845
2930883 | 지상 3층 | 지상 3층 | 2927264 | 729 | 0.19225 | 0.00729 | 0.3845
2930884 | 지상 3층 | 지상 3층 | 2927264 | 950 | 0.2475 | 0.0095 | 0.485
2930885 | 지상 3층 | 지상 3층 | 2927264 | 600 | 0.16 | 0.006 | 0.3
2930886 | 지상 3층 | 지상 3층 | 2927264 | 1070 | 0.2775 | 0.0107 | 0.545
2930918 | 지상 3층 | 지상 3층 | 2927264 | 729 | 0.19225 | 0.00729 | 0.3845
2930919 | 지상 3층 | 지상 3층 | 2927264 | 729 | 0.19225 | 0.00729 | 0.3845
2930920 | 지상 3층 | 지상 3층 | 2927264 | 729 | 0.19225 | 0.00729 | 0.3845
2930921 | 지상 3층 | 지상 3층 | 2927264 | 729 | 0.19225 | 0.00729 | 0.3845
2930922 | 지상 3층 | 지상 3층 | 2927264 | 950 | 0.2475 | 0.0095 | 0.485
2930923 | 지상 3층 | 지상 3층 | 2927264 | 600 | 0.16 | 0.006 | 0.3
2930924 | 지상 3층 | 지상 3층 | 2927264 | 1070 | 0.2775 | 0.0107 | 0.545
2930956 | 지상 3층 | 지상 3층 | 2927264 | 729 | 0.19225 | 0.00729 | 0.3845
2930957 | 지상 3층 | 지상 3층 | 2927264 | 789 | 0.20725 | 0.00789 | 0.4145
2930958 | 지상 3층 | 지상 3층 | 2927264 | 789 | 0.20725 | 0.00789 | 0.4145
2930959 | 지상 3층 | 지상 3층 | 2927264 | 789 | 0.20725 | 0.00789 | 0.4145
2930960 | 지상 3층 | 지상 3층 | 2927264 | 950 | 0.2475 | 0.0095 | 0.485
2930961 | 지상 3층 | 지상 3층 | 2927264 | 600 | 0.16 | 0.006 | 0.3
2930962 | 지상 3층 | 지상 3층 | 2927264 | 1070 | 0.2775 | 0.0107 | 0.545
2931000 | 지상 3층 | 지상 3층 | 2927264 | 789 | 0.20725 | 0.00789 | 0.4145
2931001 | 지상 3층 | 지상 3층 | 2927264 | 1000 | 0.26 | 0.01 | 0.52
2931002 | 지상 3층 | 지상 3층 | 2927264 | 1000 | 0.26 | 0.01 | 0.52
2931003 | 지상 3층 | 지상 3층 | 2927264 | 1000 | 0.26 | 0.01 | 0.52
2931004 | 지상 3층 | 지상 3층 | 2927264 | 950 | 0.2475 | 0.0095 | 0.485
2931005 | 지상 3층 | 지상 3층 | 2927264 | 600 | 0.16 | 0.006 | 0.3
2931006 | 지상 3층 | 지상 3층 | 2927264 | 1070 | 0.2775 | 0.0107 | 0.545
2931079 | 지상 3층 | 지상 3층 | 2927264 | 776 | 0.204 | 0.00776 | 0.408
2931080 | 지상 3층 | 지상 3층 | 2927264 | 716 | 0.189 | 0.00716 | 0.378
2931081 | 지상 3층 | 지상 3층 | 2927264 | 716 | 0.189 | 0.00716 | 0.378
2931082 | 지상 3층 | 지상 3층 | 2927264 | 716 | 0.189 | 0.00716 | 0.378
2931083 | 지상 3층 | 지상 3층 | 2927264 | 950 | 0.2475 | 0.0095 | 0.485
2931084 | 지상 3층 | 지상 3층 | 2927264 | 600 | 0.16 | 0.006 | 0.3
2931085 | 지상 3층 | 지상 3층 | 2927264 | 1070 | 0.2775 | 0.0107 | 0.545
2931119 | 지상 3층 | 지상 3층 | 2927264 | 776 | 0.204 | 0.00776 | 0.408
2931120 | 지상 3층 | 지상 3층 | 2927264 | 776 | 0.204 | 0.00776 | 0.408
2931121 | 지상 3층 | 지상 3층 | 2927264 | 776 | 0.204 | 0.00776 | 0.408
2931122 | 지상 3층 | 지상 3층 | 2927264 | 1000 | 0.26 | 0.01 | 0.52
2931123 | 지상 3층 | 지상 3층 | 2927264 | 950 | 0.2475 | 0.0095 | 0.485
2931124 | 지상 3층 | 지상 3층 | 2927264 | 600 | 0.16 | 0.006 | 0.3
2931125 | 지상 3층 | 지상 3층 | 2927264 | 1070 | 0.2775 | 0.0107 | 0.545
2931157 | 지상 3층 | 지상 3층 | 2927264 | 716 | 0.189 | 0.00716 | 0.378
2931158 | 지상 3층 | 지상 3층 | 2927264 | 716 | 0.189 | 0.00716 | 0.378
2931159 | 지상 3층 | 지상 3층 | 2927264 | 716 | 0.189 | 0.00716 | 0.378
2931160 | 지상 3층 | 지상 3층 | 2927264 | 716 | 0.189 | 0.00716 | 0.378
2931161 | 지상 3층 | 지상 3층 | 2927264 | 950 | 0.2475 | 0.0095 | 0.485
2931162 | 지상 3층 | 지상 3층 | 2927264 | 600 | 0.16 | 0.006 | 0.3
2931163 | 지상 3층 | 지상 3층 | 2927264 | 1070 | 0.2775 | 0.0107 | 0.545
2931195 | 지상 3층 | 지상 3층 | 2927264 | 716 | 0.189 | 0.00716 | 0.378
2931196 | 지상 3층 | 지상 3층 | 2927264 | 716 | 0.189 | 0.00716 | 0.378
2931197 | 지상 3층 | 지상 3층 | 2927264 | 716 | 0.189 | 0.00716 | 0.378
2931198 | 지상 3층 | 지상 3층 | 2927264 | 716 | 0.189 | 0.00716 | 0.378
2931199 | 지상 3층 | 지상 3층 | 2927264 | 950 | 0.2475 | 0.0095 | 0.485
2931200 | 지상 3층 | 지상 3층 | 2927264 | 600 | 0.16 | 0.006 | 0.3
2931201 | 지상 3층 | 지상 3층 | 2927264 | 1070 | 0.2775 | 0.0107 | 0.545
2931233 | 지상 3층 | 지상 3층 | 2927264 | 716 | 0.189 | 0.00716 | 0.378
2931234 | 지상 3층 | 지상 3층 | 2927264 | 716 | 0.189 | 0.00716 | 0.378
2931235 | 지상 3층 | 지상 3층 | 2927264 | 716 | 0.189 | 0.00716 | 0.378
2931236 | 지상 3층 | 지상 3층 | 2927264 | 716 | 0.189 | 0.00716 | 0.378
2931271 | 지상 3층 | 지상 3층 | 2927264 | 716 | 0.189 | 0.00716 | 0.378
2931272 | 지상 3층 | 지상 3층 | 2927264 | 776 | 0.204 | 0.00776 | 0.408
2931273 | 지상 3층 | 지상 3층 | 2927264 | 776 | 0.204 | 0.00776 | 0.408
2931274 | 지상 3층 | 지상 3층 | 2927264 | 776 | 0.204 | 0.00776 | 0.408
2931275 | 지상 3층 | 지상 3층 | 2927264 | 950 | 0.2475 | 0.0095 | 0.485
2931276 | 지상 3층 | 지상 3층 | 2927264 | 600 | 0.16 | 0.006 | 0.3
2931277 | 지상 3층 | 지상 3층 | 2927264 | 1070 | 0.2775 | 0.0107 | 0.545
2931312 | 지상 3층 | 지상 3층 | 2927264 | 990 | 0.2575 | 0.0099 | 0.515
2931313 | 지상 3층 | 지상 3층 | 2927264 | 786 | 0.2065 | 0.00786 | 0.413
2931314 | 지상 3층 | 지상 3층 | 2927264 | 786 | 0.2065 | 0.00786 | 0.413
2931315 | 지상 3층 | 지상 3층 | 2927264 | 786 | 0.2065 | 0.00786 | 0.413
2931316 | 지상 3층 | 지상 3층 | 2927264 | 950 | 0.2475 | 0.0095 | 0.485
2931317 | 지상 3층 | 지상 3층 | 2927264 | 600 | 0.16 | 0.006 | 0.3
2931318 | 지상 3층 | 지상 3층 | 2927264 | 1070 | 0.2775 | 0.0107 | 0.545
2931391 | 지상 3층 | 지상 3층 | 2927264 | 786 | 0.2065 | 0.00786 | 0.413
2931392 | 지상 3층 | 지상 3층 | 2927264 | 716 | 0.189 | 0.00716 | 0.378
2931393 | 지상 3층 | 지상 3층 | 2927264 | 716 | 0.189 | 0.00716 | 0.378
2931394 | 지상 3층 | 지상 3층 | 2927264 | 716 | 0.189 | 0.00716 | 0.378
2931395 | 지상 3층 | 지상 3층 | 2927264 | 950 | 0.2475 | 0.0095 | 0.485
2931396 | 지상 3층 | 지상 3층 | 2927264 | 600 | 0.16 | 0.006 | 0.3
2931397 | 지상 3층 | 지상 3층 | 2927264 | 1070 | 0.2775 | 0.0107 | 0.545
2931429 | 지상 3층 | 지상 3층 | 2927264 | 716 | 0.189 | 0.00716 | 0.378
2931430 | 지상 3층 | 지상 3층 | 2927264 | 716 | 0.189 | 0.00716 | 0.378
2931431 | 지상 3층 | 지상 3층 | 2927264 | 716 | 0.189 | 0.00716 | 0.378
2931432 | 지상 3층 | 지상 3층 | 2927264 | 716 | 0.189 | 0.00716 | 0.378
2931433 | 지상 3층 | 지상 3층 | 2927264 | 950 | 0.2475 | 0.0095 | 0.485
2931434 | 지상 3층 | 지상 3층 | 2927264 | 600 | 0.16 | 0.006 | 0.3
2931435 | 지상 3층 | 지상 3층 | 2927264 | 1070 | 0.2775 | 0.0107 | 0.545
2931505 | 지상 3층 | 지상 3층 | 2927264 | 716 | 0.189 | 0.00716 | 0.378
2931506 | 지상 3층 | 지상 3층 | 2927264 | 716 | 0.189 | 0.00716 | 0.378
2931507 | 지상 3층 | 지상 3층 | 2927264 | 716 | 0.189 | 0.00716 | 0.378
2931508 | 지상 3층 | 지상 3층 | 2927264 | 716 | 0.189 | 0.00716 | 0.378
2931509 | 지상 3층 | 지상 3층 | 2927264 | 950 | 0.2475 | 0.0095 | 0.485
2931510 | 지상 3층 | 지상 3층 | 2927264 | 600 | 0.16 | 0.006 | 0.3
2931511 | 지상 3층 | 지상 3층 | 2927264 | 1070 | 0.2775 | 0.0107 | 0.545
2931543 | 지상 3층 | 지상 3층 | 2927264 | 716 | 0.189 | 0.00716 | 0.378
2931544 | 지상 3층 | 지상 3층 | 2927264 | 642 | 0.1705 | 0.00642 | 0.341
2931545 | 지상 3층 | 지상 3층 | 2927264 | 642 | 0.1705 | 0.00642 | 0.341
2931546 | 지상 3층 | 지상 3층 | 2927264 | 642 | 0.1705 | 0.00642 | 0.341
2931547 | 지상 3층 | 지상 3층 | 2927264 | 950 | 0.2475 | 0.0095 | 0.485
2931548 | 지상 3층 | 지상 3층 | 2927264 | 600 | 0.16 | 0.006 | 0.3
2931549 | 지상 3층 | 지상 3층 | 2927264 | 1070 | 0.2775 | 0.0107 | 0.545
2931581 | 지상 3층 | 지상 3층 | 2927264 | 642 | 0.1705 | 0.00642 | 0.341
2931582 | 지상 3층 | 지상 3층 | 2927264 | 733 | 0.19325 | 0.00733 | 0.3865
2931583 | 지상 3층 | 지상 3층 | 2927264 | 733 | 0.19325 | 0.00733 | 0.3865
2931584 | 지상 3층 | 지상 3층 | 2927264 | 733 | 0.19325 | 0.00733 | 0.3865
2931585 | 지상 3층 | 지상 3층 | 2927264 | 950 | 0.2475 | 0.0095 | 0.485
2931586 | 지상 3층 | 지상 3층 | 2927264 | 600 | 0.16 | 0.006 | 0.3
2931587 | 지상 3층 | 지상 3층 | 2927264 | 1070 | 0.2775 | 0.0107 | 0.545
2931619 | 지상 3층 | 지상 3층 | 2927264 | 733 | 0.19325 | 0.00733 | 0.3865
2931620 | 지상 3층 | 지상 3층 | 2927264 | 912.5 | 0.238125 | 0.009125 | 0.47625
2931621 | 지상 3층 | 지상 3층 | 2927264 | 912.5 | 0.238125 | 0.009125 | 0.47625
2931622 | 지상 3층 | 지상 3층 | 2927264 | 912.5 | 0.238125 | 0.009125 | 0.47625
2931623 | 지상 3층 | 지상 3층 | 2927264 | 950 | 0.2475 | 0.0095 | 0.485
2931624 | 지상 3층 | 지상 3층 | 2927264 | 600 | 0.16 | 0.006 | 0.3
2931625 | 지상 3층 | 지상 3층 | 2927264 | 1070 | 0.2775 | 0.0107 | 0.545
2932005 | 지상 3층 | 지상 3층 | 2927264 | 804 | 0.211 | 0.00804 | 0.422
2932056 | 지상 3층 | 지상 3층 | 2927264 | 804 | 0.211 | 0.00804 | 0.422
2932057 | 지상 3층 | 지상 3층 | 2927264 | 804 | 0.211 | 0.00804 | 0.422
2932058 | 지상 3층 | 지상 3층 | 2927264 | 804 | 0.211 | 0.00804 | 0.422
2932140 | 지상 3층 | 지상 3층 | 2927264 | 804 | 0.211 | 0.00804 | 0.422
2932141 | 지상 3층 | 지상 3층 | 2927264 | 804 | 0.211 | 0.00804 | 0.422
2932142 | 지상 3층 | 지상 3층 | 2927264 | 804 | 0.211 | 0.00804 | 0.422
2933170 | 지상 3층 | 지상 3층 | 2927264 | 716 | 0.189 | 0.00716 | 0.378
2933171 | 지상 3층 | 지상 3층 | 2927264 | 716 | 0.189 | 0.00716 | 0.378
2933172 | 지상 3층 | 지상 3층 | 2927264 | 716 | 0.189 | 0.00716 | 0.378
2933173 | 지상 3층 | 지상 3층 | 2927264 | 716 | 0.189 | 0.00716 | 0.378
2933174 | 지상 3층 | 지상 3층 | 2927264 | 950 | 0.2475 | 0.0095 | 0.485
2933175 | 지상 3층 | 지상 3층 | 2927264 | 600 | 0.16 | 0.006 | 0.3
2933176 | 지상 3층 | 지상 3층 | 2927264 | 1070 | 0.2775 | 0.0107 | 0.545
2933203 | 지상 3층 | 지상 3층 | 2927264 | 716 | 0.189 | 0.00716 | 0.378
2933204 | 지상 3층 | 지상 3층 | 2927264 | 716 | 0.189 | 0.00716 | 0.378
2933205 | 지상 3층 | 지상 3층 | 2927264 | 716 | 0.189 | 0.00716 | 0.378
2933206 | 지상 3층 | 지상 3층 | 2927264 | 716 | 0.189 | 0.00716 | 0.378
2933207 | 지상 3층 | 지상 3층 | 2927264 | 950 | 0.2475 | 0.0095 | 0.485
2933208 | 지상 3층 | 지상 3층 | 2927264 | 600 | 0.16 | 0.006 | 0.3
2933209 | 지상 3층 | 지상 3층 | 2927264 | 1070 | 0.2775 | 0.0107 | 0.545
2933238 | 지상 3층 | 지상 3층 | 2927264 | 716 | 0.189 | 0.00716 | 0.378
2933239 | 지상 3층 | 지상 3층 | 2927264 | 716 | 0.189 | 0.00716 | 0.378
2933240 | 지상 3층 | 지상 3층 | 2927264 | 716 | 0.189 | 0.00716 | 0.378
2933241 | 지상 3층 | 지상 3층 | 2927264 | 716 | 0.189 | 0.00716 | 0.378
2933242 | 지상 3층 | 지상 3층 | 2927264 | 950 | 0.2475 | 0.0095 | 0.485
2933243 | 지상 3층 | 지상 3층 | 2927264 | 600 | 0.16 | 0.006 | 0.3
2933244 | 지상 3층 | 지상 3층 | 2927264 | 1070 | 0.2775 | 0.0107 | 0.545
2933273 | 지상 3층 | 지상 3층 | 2927264 | 716 | 0.189 | 0.00716 | 0.378
2933274 | 지상 3층 | 지상 3층 | 2927264 | 716 | 0.189 | 0.00716 | 0.378
2933275 | 지상 3층 | 지상 3층 | 2927264 | 716 | 0.189 | 0.00716 | 0.378
2933276 | 지상 3층 | 지상 3층 | 2927264 | 716 | 0.189 | 0.00716 | 0.378
2933277 | 지상 3층 | 지상 3층 | 2927264 | 950 | 0.2475 | 0.0095 | 0.485
2933278 | 지상 3층 | 지상 3층 | 2927264 | 600 | 0.16 | 0.006 | 0.3
2933279 | 지상 3층 | 지상 3층 | 2927264 | 1070 | 0.2775 | 0.0107 | 0.545
2933306 | 지상 3층 | 지상 3층 | 2927264 | 716 | 0.189 | 0.00716 | 0.378
2933307 | 지상 3층 | 지상 3층 | 2927264 | 716 | 0.189 | 0.00716 | 0.378
2933308 | 지상 3층 | 지상 3층 | 2927264 | 716 | 0.189 | 0.00716 | 0.378
2933309 | 지상 3층 | 지상 3층 | 2927264 | 716 | 0.189 | 0.00716 | 0.378
2933310 | 지상 3층 | 지상 3층 | 2927264 | 950 | 0.2475 | 0.0095 | 0.485
2933311 | 지상 3층 | 지상 3층 | 2927264 | 600 | 0.16 | 0.006 | 0.3
2933312 | 지상 3층 | 지상 3층 | 2927264 | 1070 | 0.2775 | 0.0107 | 0.545
2933345 | 지상 3층 | 지상 3층 | 2927264 | 950 | 0.2475 | 0.0095 | 0.485
2933346 | 지상 3층 | 지상 3층 | 2927264 | 600 | 0.16 | 0.006 | 0.3
2933347 | 지상 3층 | 지상 3층 | 2927264 | 1070 | 0.2775 | 0.0107 | 0.545
2933376 | 지상 3층 | 지상 3층 | 2927264 | 716 | 0.189 | 0.00716 | 0.378
2933377 | 지상 3층 | 지상 3층 | 2927264 | 716 | 0.189 | 0.00716 | 0.378
2933378 | 지상 3층 | 지상 3층 | 2927264 | 716 | 0.189 | 0.00716 | 0.378
2933379 | 지상 3층 | 지상 3층 | 2927264 | 716 | 0.189 | 0.00716 | 0.378
2933380 | 지상 3층 | 지상 3층 | 2927264 | 950 | 0.2475 | 0.0095 | 0.485
2933381 | 지상 3층 | 지상 3층 | 2927264 | 600 | 0.16 | 0.006 | 0.3
2933382 | 지상 3층 | 지상 3층 | 2927264 | 1070 | 0.2775 | 0.0107 | 0.545
2933409 | 지상 3층 | 지상 3층 | 2927264 | 716 | 0.189 | 0.00716 | 0.378
2933410 | 지상 3층 | 지상 3층 | 2927264 | 716 | 0.189 | 0.00716 | 0.378
2933411 | 지상 3층 | 지상 3층 | 2927264 | 716 | 0.189 | 0.00716 | 0.378
2933412 | 지상 3층 | 지상 3층 | 2927264 | 716 | 0.189 | 0.00716 | 0.378
2933413 | 지상 3층 | 지상 3층 | 2927264 | 950 | 0.2475 | 0.0095 | 0.485
2933414 | 지상 3층 | 지상 3층 | 2927264 | 600 | 0.16 | 0.006 | 0.3
2933415 | 지상 3층 | 지상 3층 | 2927264 | 1070 | 0.2775 | 0.0107 | 0.545
2933444 | 지상 3층 | 지상 3층 | 2927264 | 716 | 0.189 | 0.00716 | 0.378
2933445 | 지상 3층 | 지상 3층 | 2927264 | 716 | 0.189 | 0.00716 | 0.378
2933446 | 지상 3층 | 지상 3층 | 2927264 | 716 | 0.189 | 0.00716 | 0.378
2933447 | 지상 3층 | 지상 3층 | 2927264 | 716 | 0.189 | 0.00716 | 0.378
2933448 | 지상 3층 | 지상 3층 | 2927264 | 950 | 0.2475 | 0.0095 | 0.485
2933449 | 지상 3층 | 지상 3층 | 2927264 | 600 | 0.16 | 0.006 | 0.3
2933450 | 지상 3층 | 지상 3층 | 2927264 | 1070 | 0.2775 | 0.0107 | 0.545
2934138 | 지상 3층 | 지상 3층 | 2927264 | 716 | 0.189 | 0.00716 | 0.378
2934139 | 지상 3층 | 지상 3층 | 2927264 | 716 | 0.189 | 0.00716 | 0.378
2934140 | 지상 3층 | 지상 3층 | 2927264 | 716 | 0.189 | 0.00716 | 0.378
2934141 | 지상 3층 | 지상 3층 | 2927264 | 716 | 0.189 | 0.00716 | 0.378
2934142 | 지상 3층 | 지상 3층 | 2927264 | 950 | 0.2475 | 0.0095 | 0.485
2934143 | 지상 3층 | 지상 3층 | 2927264 | 600 | 0.16 | 0.006 | 0.3
2934144 | 지상 3층 | 지상 3층 | 2927264 | 1070 | 0.2775 | 0.0107 | 0.545
2934173 | 지상 3층 | 지상 3층 | 2927264 | 716 | 0.189 | 0.00716 | 0.378
2934174 | 지상 3층 | 지상 3층 | 2927264 | 716 | 0.189 | 0.00716 | 0.378
2934175 | 지상 3층 | 지상 3층 | 2927264 | 716 | 0.189 | 0.00716 | 0.378
2934176 | 지상 3층 | 지상 3층 | 2927264 | 716 | 0.189 | 0.00716 | 0.378
2934177 | 지상 3층 | 지상 3층 | 2927264 | 950 | 0.2475 | 0.0095 | 0.485
2934178 | 지상 3층 | 지상 3층 | 2927264 | 600 | 0.16 | 0.006 | 0.3
2934179 | 지상 3층 | 지상 3층 | 2927264 | 1070 | 0.2775 | 0.0107 | 0.545
2935125 | 지상 3층 | 지상 3층 | 2927264 | 990 | 0.2575 | 0.0099 | 0.515
2935126 | 지상 3층 | 지상 3층 | 2927264 | 990 | 0.2575 | 0.0099 | 0.515
2935127 | 지상 3층 | 지상 3층 | 2927264 | 990 | 0.2575 | 0.0099 | 0.515
2935128 | 지상 3층 | 지상 3층 | 2927264 | 776 | 0.204 | 0.00776 | 0.408
2935129 | 지상 3층 | 지상 3층 | 2927264 | 950 | 0.2475 | 0.0095 | 0.485
2935130 | 지상 3층 | 지상 3층 | 2927264 | 600 | 0.16 | 0.006 | 0.3
2935131 | 지상 3층 | 지상 3층 | 2927264 | 1070 | 0.2775 | 0.0107 | 0.545
2936726 | 지상 4층 | 지상 4층 | 2936724 | 912.5 | 0.238125 | 0.009125 | 0.47625
2936729 | 지상 4층 | 지상 4층 | 2936724 | 1100 | 0.285 | 0.011 | 0.56
2936733 | 지상 4층 | 지상 4층 | 2936724 | 600 | 0.16 | 0.006 | 0.3
2936738 | 지상 4층 | 지상 4층 | 2936724 | 950 | 0.2475 | 0.0095 | 0.475
2937027 | 지상 4층 | 지상 4층 | 2936724 | 716 | 0.189 | 0.00716 | 0.378
2937029 | 지상 4층 | 지상 4층 | 2936724 | 716 | 0.189 | 0.00716 | 0.378
2937030 | 지상 4층 | 지상 4층 | 2936724 | 716 | 0.189 | 0.00716 | 0.378
2937031 | 지상 4층 | 지상 4층 | 2936724 | 1450 | 0.3725 | 0.0145 | 0.735
2937032 | 지상 4층 | 지상 4층 | 2936724 | 600 | 0.16 | 0.006 | 0.3
2937033 | 지상 4층 | 지상 4층 | 2936724 | 1100 | 0.285 | 0.011 | 0.56
2937038 | 지상 4층 | 지상 4층 | 2936724 | 716 | 0.189 | 0.00716 | 0.378
2937040 | 지상 4층 | 지상 4층 | 2936724 | 642 | 0.1705 | 0.00642 | 0.341
2937041 | 지상 4층 | 지상 4층 | 2936724 | 642 | 0.1705 | 0.00642 | 0.341
2937042 | 지상 4층 | 지상 4층 | 2936724 | 1450 | 0.3725 | 0.0145 | 0.735
2937043 | 지상 4층 | 지상 4층 | 2936724 | 600 | 0.16 | 0.006 | 0.3
2937044 | 지상 4층 | 지상 4층 | 2936724 | 1100 | 0.285 | 0.011 | 0.56
2937049 | 지상 4층 | 지상 4층 | 2936724 | 642 | 0.1705 | 0.00642 | 0.341
2937051 | 지상 4층 | 지상 4층 | 2936724 | 733 | 0.19325 | 0.00733 | 0.3865
2937052 | 지상 4층 | 지상 4층 | 2936724 | 733 | 0.19325 | 0.00733 | 0.3865
2937053 | 지상 4층 | 지상 4층 | 2936724 | 1450 | 0.3725 | 0.0145 | 0.735
2937054 | 지상 4층 | 지상 4층 | 2936724 | 600 | 0.16 | 0.006 | 0.3
2937055 | 지상 4층 | 지상 4층 | 2936724 | 1100 | 0.285 | 0.011 | 0.56
2937060 | 지상 4층 | 지상 4층 | 2936724 | 733 | 0.19325 | 0.00733 | 0.3865
2937062 | 지상 4층 | 지상 4층 | 2936724 | 912.5 | 0.238125 | 0.009125 | 0.47625
2937063 | 지상 4층 | 지상 4층 | 2936724 | 912.5 | 0.238125 | 0.009125 | 0.47625
2937064 | 지상 4층 | 지상 4층 | 2936724 | 1450 | 0.3725 | 0.0145 | 0.735
2937065 | 지상 4층 | 지상 4층 | 2936724 | 600 | 0.16 | 0.006 | 0.3
2937066 | 지상 4층 | 지상 4층 | 2936724 | 1100 | 0.285 | 0.011 | 0.56
2937079 | 지상 4층 | 지상 4층 | 2936724 | 716 | 0.189 | 0.00716 | 0.378
2937080 | 지상 4층 | 지상 4층 | 2936724 | 716 | 0.189 | 0.00716 | 0.378
2937081 | 지상 4층 | 지상 4층 | 2936724 | 716 | 0.189 | 0.00716 | 0.378
2937082 | 지상 4층 | 지상 4층 | 2936724 | 1450 | 0.3725 | 0.0145 | 0.735
2937083 | 지상 4층 | 지상 4층 | 2936724 | 600 | 0.16 | 0.006 | 0.3
2937084 | 지상 4층 | 지상 4층 | 2936724 | 1100 | 0.285 | 0.011 | 0.56
2937090 | 지상 4층 | 지상 4층 | 2936724 | 716 | 0.189 | 0.00716 | 0.378
2937091 | 지상 4층 | 지상 4층 | 2936724 | 716 | 0.189 | 0.00716 | 0.378
2937092 | 지상 4층 | 지상 4층 | 2936724 | 716 | 0.189 | 0.00716 | 0.378
2937093 | 지상 4층 | 지상 4층 | 2936724 | 1450 | 0.3725 | 0.0145 | 0.735
2937094 | 지상 4층 | 지상 4층 | 2936724 | 600 | 0.16 | 0.006 | 0.3
2937095 | 지상 4층 | 지상 4층 | 2936724 | 1100 | 0.285 | 0.011 | 0.56
2937101 | 지상 4층 | 지상 4층 | 2936724 | 716 | 0.189 | 0.00716 | 0.378
2937102 | 지상 4층 | 지상 4층 | 2936724 | 716 | 0.189 | 0.00716 | 0.378
2937103 | 지상 4층 | 지상 4층 | 2936724 | 716 | 0.189 | 0.00716 | 0.378
2937104 | 지상 4층 | 지상 4층 | 2936724 | 1450 | 0.3725 | 0.0145 | 0.735
2937105 | 지상 4층 | 지상 4층 | 2936724 | 600 | 0.16 | 0.006 | 0.3
2937106 | 지상 4층 | 지상 4층 | 2936724 | 1100 | 0.285 | 0.011 | 0.56
2937112 | 지상 4층 | 지상 4층 | 2936724 | 716 | 0.189 | 0.00716 | 0.378
2937113 | 지상 4층 | 지상 4층 | 2936724 | 716 | 0.189 | 0.00716 | 0.378
2937114 | 지상 4층 | 지상 4층 | 2936724 | 716 | 0.189 | 0.00716 | 0.378
2937115 | 지상 4층 | 지상 4층 | 2936724 | 1450 | 0.3725 | 0.0145 | 0.735
2937116 | 지상 4층 | 지상 4층 | 2936724 | 600 | 0.16 | 0.006 | 0.3
2937117 | 지상 4층 | 지상 4층 | 2936724 | 1100 | 0.285 | 0.011 | 0.56
2937123 | 지상 4층 | 지상 4층 | 2936724 | 716 | 0.189 | 0.00716 | 0.378
2937124 | 지상 4층 | 지상 4층 | 2936724 | 716 | 0.189 | 0.00716 | 0.378
2937125 | 지상 4층 | 지상 4층 | 2936724 | 716 | 0.189 | 0.00716 | 0.378
2937126 | 지상 4층 | 지상 4층 | 2936724 | 1450 | 0.3725 | 0.0145 | 0.735
2937127 | 지상 4층 | 지상 4층 | 2936724 | 600 | 0.16 | 0.006 | 0.3
2937128 | 지상 4층 | 지상 4층 | 2936724 | 1100 | 0.285 | 0.011 | 0.56
2937545 | 지상 4층 | 지상 4층 | 2936724 | 786.395 | 0.206599 | 0.00786395 | 0.413197
2937546 | 지상 4층 | 지상 4층 | 2936724 | 786.395 | 0.206599 | 0.00786395 | 0.413197
2937981 | 지상 4층 | 지상 4층 | 2936724 | 1450 | 0.3725 | 0.0145 | 0.735
2937982 | 지상 4층 | 지상 4층 | 2936724 | 786.395 | 0.206599 | 0.00786395 | 0.413197
2937983 | 지상 4층 | 지상 4층 | 2936724 | 716 | 0.189 | 0.00716 | 0.378
2937984 | 지상 4층 | 지상 4층 | 2936724 | 716 | 0.189 | 0.00716 | 0.378
2937985 | 지상 4층 | 지상 4층 | 2936724 | 716 | 0.189 | 0.00716 | 0.378
2937986 | 지상 4층 | 지상 4층 | 2936724 | 716 | 0.189 | 0.00716 | 0.378
2937987 | 지상 4층 | 지상 4층 | 2936724 | 716 | 0.189 | 0.00716 | 0.378
2937988 | 지상 4층 | 지상 4층 | 2936724 | 716 | 0.189 | 0.00716 | 0.378
2937989 | 지상 4층 | 지상 4층 | 2936724 | 642 | 0.1705 | 0.00642 | 0.341
2937990 | 지상 4층 | 지상 4층 | 2936724 | 733 | 0.19325 | 0.00733 | 0.3865
2937991 | 지상 4층 | 지상 4층 | 2936724 | 912.5 | 0.238125 | 0.009125 | 0.47625
2937992 | 지상 4층 | 지상 4층 | 2936724 | 950 | 0.2475 | 0.0095 | 0.475
2937993 | 지상 4층 | 지상 4층 | 2936724 | 950 | 0.2475 | 0.0095 | 0.475
2937994 | 지상 4층 | 지상 4층 | 2936724 | 950 | 0.2475 | 0.0095 | 0.475
2937995 | 지상 4층 | 지상 4층 | 2936724 | 950 | 0.2475 | 0.0095 | 0.475
2937996 | 지상 4층 | 지상 4층 | 2936724 | 950 | 0.2475 | 0.0095 | 0.475
2937997 | 지상 4층 | 지상 4층 | 2936724 | 950 | 0.2475 | 0.0095 | 0.475
2937998 | 지상 4층 | 지상 4층 | 2936724 | 950 | 0.2475 | 0.0095 | 0.475
2937999 | 지상 4층 | 지상 4층 | 2936724 | 950 | 0.2475 | 0.0095 | 0.475
2938000 | 지상 4층 | 지상 4층 | 2936724 | 950 | 0.2475 | 0.0095 | 0.475
3183963 | 지상 4층 | 지상 4층 | 2936724 | 716 | 0.189 | 0.00716 | 0.378
3183965 | 지상 4층 | 지상 4층 | 2936724 | 716 | 0.189 | 0.00716 | 0.378
3183966 | 지상 4층 | 지상 4층 | 2936724 | 716 | 0.189 | 0.00716 | 0.378
3183967 | 지상 4층 | 지상 4층 | 2936724 | 716 | 0.189 | 0.00716 | 0.378
3183968 | 지상 4층 | 지상 4층 | 2936724 | 1450 | 0.3725 | 0.0145 | 0.735
3183969 | 지상 4층 | 지상 4층 | 2936724 | 950 | 0.2475 | 0.0095 | 0.475
3183970 | 지상 4층 | 지상 4층 | 2936724 | 600 | 0.16 | 0.006 | 0.3
3183971 | 지상 4층 | 지상 4층 | 2936724 | 1100 | 0.285 | 0.011 | 0.56
3184014 | 지상 4층 | 지상 4층 | 2936724 | 716 | 0.189 | 0.00716 | 0.378
3184016 | 지상 4층 | 지상 4층 | 2936724 | 716 | 0.189 | 0.00716 | 0.378
3184017 | 지상 4층 | 지상 4층 | 2936724 | 716 | 0.189 | 0.00716 | 0.378
3184018 | 지상 4층 | 지상 4층 | 2936724 | 716 | 0.189 | 0.00716 | 0.378
3184019 | 지상 4층 | 지상 4층 | 2936724 | 1450 | 0.3725 | 0.0145 | 0.735
3184020 | 지상 4층 | 지상 4층 | 2936724 | 950 | 0.2475 | 0.0095 | 0.475
3184021 | 지상 4층 | 지상 4층 | 2936724 | 600 | 0.16 | 0.006 | 0.3
3184022 | 지상 4층 | 지상 4층 | 2936724 | 1100 | 0.285 | 0.011 | 0.56
3184069 | 지상 4층 | 지상 4층 | 2936724 | 716 | 0.189 | 0.00716 | 0.378
3184071 | 지상 4층 | 지상 4층 | 2936724 | 716 | 0.189 | 0.00716 | 0.378
3184072 | 지상 4층 | 지상 4층 | 2936724 | 716 | 0.189 | 0.00716 | 0.378
3184073 | 지상 4층 | 지상 4층 | 2936724 | 716 | 0.189 | 0.00716 | 0.378
3184074 | 지상 4층 | 지상 4층 | 2936724 | 1450 | 0.3725 | 0.0145 | 0.735
3184075 | 지상 4층 | 지상 4층 | 2936724 | 950 | 0.2475 | 0.0095 | 0.475
3184076 | 지상 4층 | 지상 4층 | 2936724 | 600 | 0.16 | 0.006 | 0.3
3184077 | 지상 4층 | 지상 4층 | 2936724 | 1100 | 0.285 | 0.011 | 0.56
3184152 | 지상 4층 | 지상 4층 | 2936724 | 716 | 0.189 | 0.00716 | 0.378
3184154 | 지상 4층 | 지상 4층 | 2936724 | 716 | 0.189 | 0.00716 | 0.378
3184155 | 지상 4층 | 지상 4층 | 2936724 | 716 | 0.189 | 0.00716 | 0.378
3184156 | 지상 4층 | 지상 4층 | 2936724 | 716 | 0.189 | 0.00716 | 0.378
3184157 | 지상 4층 | 지상 4층 | 2936724 | 1450 | 0.3725 | 0.0145 | 0.735
3184158 | 지상 4층 | 지상 4층 | 2936724 | 950 | 0.2475 | 0.0095 | 0.475
3184159 | 지상 4층 | 지상 4층 | 2936724 | 600 | 0.16 | 0.006 | 0.3
3184160 | 지상 4층 | 지상 4층 | 2936724 | 1100 | 0.285 | 0.011 | 0.56
3184201 | 지상 4층 | 지상 4층 | 2936724 | 786.395 | 0.206599 | 0.00786395 | 0.413197
3184203 | 지상 4층 | 지상 4층 | 2936724 | 716 | 0.189 | 0.00716 | 0.378
3184204 | 지상 4층 | 지상 4층 | 2936724 | 716 | 0.189 | 0.00716 | 0.378
3184205 | 지상 4층 | 지상 4층 | 2936724 | 716 | 0.189 | 0.00716 | 0.378
3184206 | 지상 4층 | 지상 4층 | 2936724 | 1450 | 0.3725 | 0.0145 | 0.735
3184207 | 지상 4층 | 지상 4층 | 2936724 | 950 | 0.2475 | 0.0095 | 0.475
3184208 | 지상 4층 | 지상 4층 | 2936724 | 600 | 0.16 | 0.006 | 0.3
3184209 | 지상 4층 | 지상 4층 | 2936724 | 1100 | 0.285 | 0.011 | 0.56
2938148 | 지상 4층 | 지상 4층 | 2938145 | 178.395 | 0.0545986 | 0.00178395 | 0.109197
2938149 | 지상 4층 | 지상 4층 | 2938145 | 400 | 0.11 | 0.004 | 0.21
2938150 | 지상 4층 | 지상 4층 | 2938145 | 1100 | 0.285 | 0.011 | 0.56
2938153 | 지상 4층 | 지상 4층 | 2938145 | 1100 | 0.285 | 0.011 | 0.56
2938154 | 지상 4층 | 지상 4층 | 2938145 | 600 | 0.16 | 0.006 | 0.3
2938155 | 지상 4층 | 지상 4층 | 2938145 | 178.395 | 0.0545986 | 0.00178395 | 0.109197
2938158 | 지상 4층 | 지상 4층 | 2938145 | 600 | 0.16 | 0.006 | 0.3
2938159 | 지상 4층 | 지상 4층 | 2938145 | 400 | 0.11 | 0.004 | 0.21
2938160 | 지상 4층 | 지상 4층 | 2938145 | 178.395 | 0.0545986 | 0.00178395 | 0.109197
2938165 | 지상 4층 | 지상 4층 | 2938145 | 178.395 | 0.0545986 | 0.00178395 | 0.109197
2938166 | 지상 4층 | 지상 4층 | 2938145 | 803.5 | 0.210875 | 0.008035 | 0.42175
2938167 | 지상 4층 | 지상 4층 | 2938145 | 803.5 | 0.210875 | 0.008035 | 0.42175
2938168 | 지상 4층 | 지상 4층 | 2938145 | 803.5 | 0.210875 | 0.008035 | 0.42175
2938169 | 지상 4층 | 지상 4층 | 2938145 | 400 | 0.11 | 0.004 | 0.21
2938170 | 지상 4층 | 지상 4층 | 2938145 | 600 | 0.16 | 0.006 | 0.3
2938171 | 지상 4층 | 지상 4층 | 2938145 | 1100 | 0.285 | 0.011 | 0.56
2938176 | 지상 4층 | 지상 4층 | 2938145 | 803.5 | 0.210875 | 0.008035 | 0.42175
2938177 | 지상 4층 | 지상 4층 | 2938145 | 803.5 | 0.210875 | 0.008035 | 0.42175
2938178 | 지상 4층 | 지상 4층 | 2938145 | 803.5 | 0.210875 | 0.008035 | 0.42175
2938179 | 지상 4층 | 지상 4층 | 2938145 | 803.5 | 0.210875 | 0.008035 | 0.42175
2938180 | 지상 4층 | 지상 4층 | 2938145 | 400 | 0.11 | 0.004 | 0.21
2938181 | 지상 4층 | 지상 4층 | 2938145 | 600 | 0.16 | 0.006 | 0.3
2938182 | 지상 4층 | 지상 4층 | 2938145 | 1100 | 0.285 | 0.011 | 0.56
2938183 | 지상 4층 | 지상 4층 | 2938145 | 803.5 | 0.210875 | 0.008035 | 0.42175
2938188 | 지상 4층 | 지상 4층 | 2938145 | 400 | 0.11 | 0.004 | 0.21
2938189 | 지상 4층 | 지상 4층 | 2938145 | 600 | 0.16 | 0.006 | 0.3
2938190 | 지상 4층 | 지상 4층 | 2938145 | 1100 | 0.285 | 0.011 | 0.56
2938195 | 지상 4층 | 지상 4층 | 2938145 | 400 | 0.11 | 0.004 | 0.21
2938196 | 지상 4층 | 지상 4층 | 2938145 | 600 | 0.16 | 0.006 | 0.3
2938197 | 지상 4층 | 지상 4층 | 2938145 | 1100 | 0.285 | 0.011 | 0.56
2938202 | 지상 4층 | 지상 4층 | 2938145 | 803.5 | 0.210875 | 0.008035 | 0.42175
2938203 | 지상 4층 | 지상 4층 | 2938145 | 803.5 | 0.210875 | 0.008035 | 0.42175
2938204 | 지상 4층 | 지상 4층 | 2938145 | 803.5 | 0.210875 | 0.008035 | 0.42175
2938205 | 지상 4층 | 지상 4층 | 2938145 | 803.5 | 0.210875 | 0.008035 | 0.42175
2938206 | 지상 4층 | 지상 4층 | 2938145 | 400 | 0.11 | 0.004 | 0.21
2938207 | 지상 4층 | 지상 4층 | 2938145 | 600 | 0.16 | 0.006 | 0.3
2938208 | 지상 4층 | 지상 4층 | 2938145 | 1100 | 0.285 | 0.011 | 0.56
2938213 | 지상 4층 | 지상 4층 | 2938145 | 803.5 | 0.210875 | 0.008035 | 0.42175
2938214 | 지상 4층 | 지상 4층 | 2938145 | 803.5 | 0.210875 | 0.008035 | 0.42175
2938215 | 지상 4층 | 지상 4층 | 2938145 | 803.5 | 0.210875 | 0.008035 | 0.42175
2938216 | 지상 4층 | 지상 4층 | 2938145 | 803.5 | 0.210875 | 0.008035 | 0.42175
2938217 | 지상 4층 | 지상 4층 | 2938145 | 400 | 0.11 | 0.004 | 0.21
2938218 | 지상 4층 | 지상 4층 | 2938145 | 600 | 0.16 | 0.006 | 0.3
2938219 | 지상 4층 | 지상 4층 | 2938145 | 1100 | 0.285 | 0.011 | 0.56
2938224 | 지상 4층 | 지상 4층 | 2938145 | 803.5 | 0.210875 | 0.008035 | 0.42175
2938225 | 지상 4층 | 지상 4층 | 2938145 | 803.5 | 0.210875 | 0.008035 | 0.42175
2938226 | 지상 4층 | 지상 4층 | 2938145 | 803.5 | 0.210875 | 0.008035 | 0.42175
2938227 | 지상 4층 | 지상 4층 | 2938145 | 803.5 | 0.210875 | 0.008035 | 0.42175
2938228 | 지상 4층 | 지상 4층 | 2938145 | 400 | 0.11 | 0.004 | 0.21
2938229 | 지상 4층 | 지상 4층 | 2938145 | 600 | 0.16 | 0.006 | 0.3
2938230 | 지상 4층 | 지상 4층 | 2938145 | 1100 | 0.285 | 0.011 | 0.56
2938235 | 지상 4층 | 지상 4층 | 2938145 | 803.5 | 0.210875 | 0.008035 | 0.42175
2938236 | 지상 4층 | 지상 4층 | 2938145 | 803.5 | 0.210875 | 0.008035 | 0.42175
2938237 | 지상 4층 | 지상 4층 | 2938145 | 803.5 | 0.210875 | 0.008035 | 0.42175
2938238 | 지상 4층 | 지상 4층 | 2938145 | 803.5 | 0.210875 | 0.008035 | 0.42175
2938239 | 지상 4층 | 지상 4층 | 2938145 | 400 | 0.11 | 0.004 | 0.21
2938240 | 지상 4층 | 지상 4층 | 2938145 | 600 | 0.16 | 0.006 | 0.3
2938241 | 지상 4층 | 지상 4층 | 2938145 | 1100 | 0.285 | 0.011 | 0.56
2938246 | 지상 4층 | 지상 4층 | 2938145 | 803.5 | 0.210875 | 0.008035 | 0.42175
2938247 | 지상 4층 | 지상 4층 | 2938145 | 1120 | 0.29 | 0.0112 | 0.58
2938248 | 지상 4층 | 지상 4층 | 2938145 | 1120 | 0.29 | 0.0112 | 0.58
2938249 | 지상 4층 | 지상 4층 | 2938145 | 1120 | 0.29 | 0.0112 | 0.58
2938250 | 지상 4층 | 지상 4층 | 2938145 | 400 | 0.11 | 0.004 | 0.21
2938251 | 지상 4층 | 지상 4층 | 2938145 | 600 | 0.16 | 0.006 | 0.3
2938252 | 지상 4층 | 지상 4층 | 2938145 | 1100 | 0.285 | 0.011 | 0.56
2938257 | 지상 4층 | 지상 4층 | 2938145 | 1120 | 0.29 | 0.0112 | 0.58
2938258 | 지상 4층 | 지상 4층 | 2938145 | 729 | 0.19225 | 0.00729 | 0.3845
2938259 | 지상 4층 | 지상 4층 | 2938145 | 729 | 0.19225 | 0.00729 | 0.3845
2938260 | 지상 4층 | 지상 4층 | 2938145 | 729 | 0.19225 | 0.00729 | 0.3845
2938261 | 지상 4층 | 지상 4층 | 2938145 | 400 | 0.11 | 0.004 | 0.21
2938262 | 지상 4층 | 지상 4층 | 2938145 | 600 | 0.16 | 0.006 | 0.3
2938263 | 지상 4층 | 지상 4층 | 2938145 | 1100 | 0.285 | 0.011 | 0.56
2938268 | 지상 4층 | 지상 4층 | 2938145 | 729 | 0.19225 | 0.00729 | 0.3845
2938269 | 지상 4층 | 지상 4층 | 2938145 | 729 | 0.19225 | 0.00729 | 0.3845
2938270 | 지상 4층 | 지상 4층 | 2938145 | 729 | 0.19225 | 0.00729 | 0.3845
2938271 | 지상 4층 | 지상 4층 | 2938145 | 729 | 0.19225 | 0.00729 | 0.3845
2938272 | 지상 4층 | 지상 4층 | 2938145 | 400 | 0.11 | 0.004 | 0.21
2938273 | 지상 4층 | 지상 4층 | 2938145 | 600 | 0.16 | 0.006 | 0.3
2938274 | 지상 4층 | 지상 4층 | 2938145 | 1100 | 0.285 | 0.011 | 0.56
2938279 | 지상 4층 | 지상 4층 | 2938145 | 729 | 0.19225 | 0.00729 | 0.3845
2938280 | 지상 4층 | 지상 4층 | 2938145 | 729 | 0.19225 | 0.00729 | 0.3845
2938281 | 지상 4층 | 지상 4층 | 2938145 | 729 | 0.19225 | 0.00729 | 0.3845
2938282 | 지상 4층 | 지상 4층 | 2938145 | 729 | 0.19225 | 0.00729 | 0.3845
2938283 | 지상 4층 | 지상 4층 | 2938145 | 400 | 0.11 | 0.004 | 0.21
2938284 | 지상 4층 | 지상 4층 | 2938145 | 600 | 0.16 | 0.006 | 0.3
2938285 | 지상 4층 | 지상 4층 | 2938145 | 1100 | 0.285 | 0.011 | 0.56
2938290 | 지상 4층 | 지상 4층 | 2938145 | 729 | 0.19225 | 0.00729 | 0.3845
2938291 | 지상 4층 | 지상 4층 | 2938145 | 729 | 0.19225 | 0.00729 | 0.3845
2938292 | 지상 4층 | 지상 4층 | 2938145 | 729 | 0.19225 | 0.00729 | 0.3845
2938293 | 지상 4층 | 지상 4층 | 2938145 | 729 | 0.19225 | 0.00729 | 0.3845
2938294 | 지상 4층 | 지상 4층 | 2938145 | 400 | 0.11 | 0.004 | 0.21
2938295 | 지상 4층 | 지상 4층 | 2938145 | 600 | 0.16 | 0.006 | 0.3
2938296 | 지상 4층 | 지상 4층 | 2938145 | 1100 | 0.285 | 0.011 | 0.56
2938301 | 지상 4층 | 지상 4층 | 2938145 | 729 | 0.19225 | 0.00729 | 0.3845
2938302 | 지상 4층 | 지상 4층 | 2938145 | 729 | 0.19225 | 0.00729 | 0.3845
2938303 | 지상 4층 | 지상 4층 | 2938145 | 729 | 0.19225 | 0.00729 | 0.3845
2938304 | 지상 4층 | 지상 4층 | 2938145 | 729 | 0.19225 | 0.00729 | 0.3845
2938305 | 지상 4층 | 지상 4층 | 2938145 | 400 | 0.11 | 0.004 | 0.21
2938306 | 지상 4층 | 지상 4층 | 2938145 | 600 | 0.16 | 0.006 | 0.3
2938307 | 지상 4층 | 지상 4층 | 2938145 | 1100 | 0.285 | 0.011 | 0.56
2938312 | 지상 4층 | 지상 4층 | 2938145 | 729 | 0.19225 | 0.00729 | 0.3845
2938313 | 지상 4층 | 지상 4층 | 2938145 | 729 | 0.19225 | 0.00729 | 0.3845
2938314 | 지상 4층 | 지상 4층 | 2938145 | 729 | 0.19225 | 0.00729 | 0.3845
2938315 | 지상 4층 | 지상 4층 | 2938145 | 729 | 0.19225 | 0.00729 | 0.3845
2938316 | 지상 4층 | 지상 4층 | 2938145 | 400 | 0.11 | 0.004 | 0.21
2938317 | 지상 4층 | 지상 4층 | 2938145 | 600 | 0.16 | 0.006 | 0.3
2938318 | 지상 4층 | 지상 4층 | 2938145 | 1100 | 0.285 | 0.011 | 0.56
2938323 | 지상 4층 | 지상 4층 | 2938145 | 729 | 0.19225 | 0.00729 | 0.3845
2938324 | 지상 4층 | 지상 4층 | 2938145 | 729 | 0.19225 | 0.00729 | 0.3845
2938325 | 지상 4층 | 지상 4층 | 2938145 | 729 | 0.19225 | 0.00729 | 0.3845
2938326 | 지상 4층 | 지상 4층 | 2938145 | 729 | 0.19225 | 0.00729 | 0.3845
2938327 | 지상 4층 | 지상 4층 | 2938145 | 400 | 0.11 | 0.004 | 0.21
2938328 | 지상 4층 | 지상 4층 | 2938145 | 600 | 0.16 | 0.006 | 0.3
2938329 | 지상 4층 | 지상 4층 | 2938145 | 1100 | 0.285 | 0.011 | 0.56
2938334 | 지상 4층 | 지상 4층 | 2938145 | 729 | 0.19225 | 0.00729 | 0.3845
2938335 | 지상 4층 | 지상 4층 | 2938145 | 729 | 0.19225 | 0.00729 | 0.3845
2938336 | 지상 4층 | 지상 4층 | 2938145 | 729 | 0.19225 | 0.00729 | 0.3845
2938337 | 지상 4층 | 지상 4층 | 2938145 | 729 | 0.19225 | 0.00729 | 0.3845
2938338 | 지상 4층 | 지상 4층 | 2938145 | 400 | 0.11 | 0.004 | 0.21
2938339 | 지상 4층 | 지상 4층 | 2938145 | 600 | 0.16 | 0.006 | 0.3
2938340 | 지상 4층 | 지상 4층 | 2938145 | 1100 | 0.285 | 0.011 | 0.56
2938345 | 지상 4층 | 지상 4층 | 2938145 | 729 | 0.19225 | 0.00729 | 0.3845
2938346 | 지상 4층 | 지상 4층 | 2938145 | 1120 | 0.29 | 0.0112 | 0.58
2938347 | 지상 4층 | 지상 4층 | 2938145 | 1120 | 0.29 | 0.0112 | 0.58
2938348 | 지상 4층 | 지상 4층 | 2938145 | 1120 | 0.29 | 0.0112 | 0.58
2938349 | 지상 4층 | 지상 4층 | 2938145 | 400 | 0.11 | 0.004 | 0.21
2938350 | 지상 4층 | 지상 4층 | 2938145 | 600 | 0.16 | 0.006 | 0.3
2938351 | 지상 4층 | 지상 4층 | 2938145 | 1100 | 0.285 | 0.011 | 0.56
2938356 | 지상 4층 | 지상 4층 | 2938145 | 716.5 | 0.189125 | 0.007165 | 0.37825
2938357 | 지상 4층 | 지상 4층 | 2938145 | 716.5 | 0.189125 | 0.007165 | 0.37825
2938358 | 지상 4층 | 지상 4층 | 2938145 | 716.5 | 0.189125 | 0.007165 | 0.37825
2938359 | 지상 4층 | 지상 4층 | 2938145 | 716.5 | 0.189125 | 0.007165 | 0.37825
2938360 | 지상 4층 | 지상 4층 | 2938145 | 400 | 0.11 | 0.004 | 0.21
2938361 | 지상 4층 | 지상 4층 | 2938145 | 600 | 0.16 | 0.006 | 0.3
2938362 | 지상 4층 | 지상 4층 | 2938145 | 1100 | 0.285 | 0.011 | 0.56
2938367 | 지상 4층 | 지상 4층 | 2938145 | 716.5 | 0.189125 | 0.007165 | 0.37825
2938368 | 지상 4층 | 지상 4층 | 2938145 | 716.5 | 0.189125 | 0.007165 | 0.37825
2938369 | 지상 4층 | 지상 4층 | 2938145 | 716.5 | 0.189125 | 0.007165 | 0.37825
2938370 | 지상 4층 | 지상 4층 | 2938145 | 1120 | 0.29 | 0.0112 | 0.58
2938371 | 지상 4층 | 지상 4층 | 2938145 | 400 | 0.11 | 0.004 | 0.21
2938372 | 지상 4층 | 지상 4층 | 2938145 | 600 | 0.16 | 0.006 | 0.3
2938373 | 지상 4층 | 지상 4층 | 2938145 | 1100 | 0.285 | 0.011 | 0.56
2938378 | 지상 4층 | 지상 4층 | 2938145 | 716.5 | 0.189125 | 0.007165 | 0.37825
2938379 | 지상 4층 | 지상 4층 | 2938145 | 716.5 | 0.189125 | 0.007165 | 0.37825
2938380 | 지상 4층 | 지상 4층 | 2938145 | 716.5 | 0.189125 | 0.007165 | 0.37825
2938381 | 지상 4층 | 지상 4층 | 2938145 | 716.5 | 0.189125 | 0.007165 | 0.37825
2938382 | 지상 4층 | 지상 4층 | 2938145 | 400 | 0.11 | 0.004 | 0.21
2938383 | 지상 4층 | 지상 4층 | 2938145 | 600 | 0.16 | 0.006 | 0.3
2938384 | 지상 4층 | 지상 4층 | 2938145 | 1100 | 0.285 | 0.011 | 0.56
2938389 | 지상 4층 | 지상 4층 | 2938145 | 716.5 | 0.189125 | 0.007165 | 0.37825
2938390 | 지상 4층 | 지상 4층 | 2938145 | 716.5 | 0.189125 | 0.007165 | 0.37825
2938391 | 지상 4층 | 지상 4층 | 2938145 | 716.5 | 0.189125 | 0.007165 | 0.37825
2938392 | 지상 4층 | 지상 4층 | 2938145 | 716.5 | 0.189125 | 0.007165 | 0.37825
2938393 | 지상 4층 | 지상 4층 | 2938145 | 400 | 0.11 | 0.004 | 0.21
2938394 | 지상 4층 | 지상 4층 | 2938145 | 600 | 0.16 | 0.006 | 0.3
2938395 | 지상 4층 | 지상 4층 | 2938145 | 1100 | 0.285 | 0.011 | 0.56
2938396 | 지상 4층 | 지상 4층 | 2938145 | 716.5 | 0.189125 | 0.007165 | 0.37825
2938397 | 지상 4층 | 지상 4층 | 2938145 | 716.5 | 0.189125 | 0.007165 | 0.37825
2938398 | 지상 4층 | 지상 4층 | 2938145 | 716.5 | 0.189125 | 0.007165 | 0.37825
2938399 | 지상 4층 | 지상 4층 | 2938145 | 716.5 | 0.189125 | 0.007165 | 0.37825
2938404 | 지상 4층 | 지상 4층 | 2938145 | 716.5 | 0.189125 | 0.007165 | 0.37825
2938405 | 지상 4층 | 지상 4층 | 2938145 | 716.5 | 0.189125 | 0.007165 | 0.37825
2938406 | 지상 4층 | 지상 4층 | 2938145 | 716.5 | 0.189125 | 0.007165 | 0.37825
2938407 | 지상 4층 | 지상 4층 | 2938145 | 716.5 | 0.189125 | 0.007165 | 0.37825
2938408 | 지상 4층 | 지상 4층 | 2938145 | 400 | 0.11 | 0.004 | 0.21
2938409 | 지상 4층 | 지상 4층 | 2938145 | 600 | 0.16 | 0.006 | 0.3
2938410 | 지상 4층 | 지상 4층 | 2938145 | 1100 | 0.285 | 0.011 | 0.56
2938419 | 지상 4층 | 지상 4층 | 2938145 | 400 | 0.11 | 0.004 | 0.21
2938420 | 지상 4층 | 지상 4층 | 2938145 | 600 | 0.16 | 0.006 | 0.3
2938421 | 지상 4층 | 지상 4층 | 2938145 | 1100 | 0.285 | 0.011 | 0.56
2938488 | 지상 4층 | 지상 4층 | 2938145 | 803.5 | 0.210875 | 0.008035 | 0.42175
2938489 | 지상 4층 | 지상 4층 | 2938145 | 803.5 | 0.210875 | 0.008035 | 0.42175
2938490 | 지상 4층 | 지상 4층 | 2938145 | 803.5 | 0.210875 | 0.008035 | 0.42175
2938491 | 지상 4층 | 지상 4층 | 2938145 | 803.5 | 0.210875 | 0.008035 | 0.42175
2938492 | 지상 4층 | 지상 4층 | 2938145 | 803.5 | 0.210875 | 0.008035 | 0.42175
2938493 | 지상 4층 | 지상 4층 | 2938145 | 803.5 | 0.210875 | 0.008035 | 0.42175
2938494 | 지상 4층 | 지상 4층 | 2938145 | 803.5 | 0.210875 | 0.008035 | 0.42175
2938594 | 지상 4층 | 지상 4층 | 2938145 | 716.5 | 0.189125 | 0.007165 | 0.37825
2938595 | 지상 4층 | 지상 4층 | 2938145 | 716.5 | 0.189125 | 0.007165 | 0.37825
2938596 | 지상 4층 | 지상 4층 | 2938145 | 716.5 | 0.189125 | 0.007165 | 0.37825
2938597 | 지상 4층 | 지상 4층 | 2938145 | 716.5 | 0.189125 | 0.007165 | 0.37825
2938598 | 지상 4층 | 지상 4층 | 2938145 | 400 | 0.11 | 0.004 | 0.21
2938599 | 지상 4층 | 지상 4층 | 2938145 | 600 | 0.16 | 0.006 | 0.3
2938600 | 지상 4층 | 지상 4층 | 2938145 | 1100 | 0.285 | 0.011 | 0.56
2938605 | 지상 4층 | 지상 4층 | 2938145 | 716.5 | 0.189125 | 0.007165 | 0.37825
2938606 | 지상 4층 | 지상 4층 | 2938145 | 716.5 | 0.189125 | 0.007165 | 0.37825
2938607 | 지상 4층 | 지상 4층 | 2938145 | 716.5 | 0.189125 | 0.007165 | 0.37825
2938608 | 지상 4층 | 지상 4층 | 2938145 | 716.5 | 0.189125 | 0.007165 | 0.37825
2938609 | 지상 4층 | 지상 4층 | 2938145 | 400 | 0.11 | 0.004 | 0.21
2938610 | 지상 4층 | 지상 4층 | 2938145 | 600 | 0.16 | 0.006 | 0.3
2938611 | 지상 4층 | 지상 4층 | 2938145 | 1100 | 0.285 | 0.011 | 0.56
2938619 | 지상 4층 | 지상 4층 | 2938145 | 716.5 | 0.189125 | 0.007165 | 0.37825
2938620 | 지상 4층 | 지상 4층 | 2938145 | 400 | 0.11 | 0.004 | 0.21
2938621 | 지상 4층 | 지상 4층 | 2938145 | 600 | 0.16 | 0.006 | 0.3
2938622 | 지상 4층 | 지상 4층 | 2938145 | 1100 | 0.285 | 0.011 | 0.56
2940513 | 지상 3층 | 지상 3층 | 2940510 | 892.808 | 0.233202 | 0.00892808 | 0.466404
2940514 | 지상 3층 | 지상 3층 | 2940510 | 912.192 | 0.238048 | 0.00912192 | 0.476096
2941420 | 지상 3층 | 지상 3층 | 2940510 | 912.192 | 0.238048 | 0.00912192 | 0.476096
2941421 | 지상 3층 | 지상 3층 | 2940510 | 945 | 0.24625 | 0.00945 | 0.4925
2941422 | 지상 3층 | 지상 3층 | 2940510 | 950 | 0.2475 | 0.0095 | 0.485
2941474 | 지상 3층 | 지상 3층 | 2940510 | 912.192 | 0.238048 | 0.00912192 | 0.476096
2941475 | 지상 3층 | 지상 3층 | 2940510 | 945 | 0.24625 | 0.00945 | 0.4925
2941476 | 지상 3층 | 지상 3층 | 2940510 | 600 | 0.16 | 0.006 | 0.3
2941533 | 지상 3층 | 지상 3층 | 2940510 | 912.192 | 0.238048 | 0.00912192 | 0.476096
2941534 | 지상 3층 | 지상 3층 | 2940510 | 945 | 0.24625 | 0.00945 | 0.4925
2941535 | 지상 3층 | 지상 3층 | 2940510 | 1070 | 0.2775 | 0.0107 | 0.535
2941590 | 지상 3층 | 지상 3층 | 2940510 | 912.192 | 0.238048 | 0.00912192 | 0.476096
2941591 | 지상 3층 | 지상 3층 | 2940510 | 945 | 0.24625 | 0.00945 | 0.4925
2941592 | 지상 3층 | 지상 3층 | 2940510 | 1480 | 0.38 | 0.0148 | 0.75
2941786 | 지상 3층 | 지상 3층 | 2940510 | 945 | 0.24625 | 0.00945 | 0.4925
2941787 | 지상 3층 | 지상 3층 | 2940510 | 915 | 0.23875 | 0.00915 | 0.4775
2941788 | 지상 3층 | 지상 3층 | 2940510 | 915 | 0.23875 | 0.00915 | 0.4775
2941789 | 지상 3층 | 지상 3층 | 2940510 | 915 | 0.23875 | 0.00915 | 0.4775
2941790 | 지상 3층 | 지상 3층 | 2940510 | 915 | 0.23875 | 0.00915 | 0.4775
2941791 | 지상 3층 | 지상 3층 | 2940510 | 950 | 0.2475 | 0.0095 | 0.485
2941792 | 지상 3층 | 지상 3층 | 2940510 | 600 | 0.16 | 0.006 | 0.3
2941793 | 지상 3층 | 지상 3층 | 2940510 | 1070 | 0.2775 | 0.0107 | 0.535
2941794 | 지상 3층 | 지상 3층 | 2940510 | 1480 | 0.38 | 0.0148 | 0.75
2941833 | 지상 3층 | 지상 3층 | 2940510 | 915 | 0.23875 | 0.00915 | 0.4775
2941834 | 지상 3층 | 지상 3층 | 2940510 | 915 | 0.23875 | 0.00915 | 0.4775
2941835 | 지상 3층 | 지상 3층 | 2940510 | 915 | 0.23875 | 0.00915 | 0.4775
2941836 | 지상 3층 | 지상 3층 | 2940510 | 915 | 0.23875 | 0.00915 | 0.4775
2941837 | 지상 3층 | 지상 3층 | 2940510 | 915 | 0.23875 | 0.00915 | 0.4775
2941838 | 지상 3층 | 지상 3층 | 2940510 | 950 | 0.2475 | 0.0095 | 0.485
2941839 | 지상 3층 | 지상 3층 | 2940510 | 600 | 0.16 | 0.006 | 0.3
2941840 | 지상 3층 | 지상 3층 | 2940510 | 1070 | 0.2775 | 0.0107 | 0.535
2941841 | 지상 3층 | 지상 3층 | 2940510 | 1480 | 0.38 | 0.0148 | 0.75
2941958 | 지상 3층 | 지상 3층 | 2940510 | 915 | 0.23875 | 0.00915 | 0.4775
2941959 | 지상 3층 | 지상 3층 | 2940510 | 915 | 0.23875 | 0.00915 | 0.4775
2941960 | 지상 3층 | 지상 3층 | 2940510 | 915 | 0.23875 | 0.00915 | 0.4775
2941961 | 지상 3층 | 지상 3층 | 2940510 | 915 | 0.23875 | 0.00915 | 0.4775
2941962 | 지상 3층 | 지상 3층 | 2940510 | 915 | 0.23875 | 0.00915 | 0.4775
2941963 | 지상 3층 | 지상 3층 | 2940510 | 950 | 0.2475 | 0.0095 | 0.485
2941964 | 지상 3층 | 지상 3층 | 2940510 | 600 | 0.16 | 0.006 | 0.3
2941965 | 지상 3층 | 지상 3층 | 2940510 | 1070 | 0.2775 | 0.0107 | 0.535
2941966 | 지상 3층 | 지상 3층 | 2940510 | 1480 | 0.38 | 0.0148 | 0.75
2942003 | 지상 3층 | 지상 3층 | 2940510 | 915 | 0.23875 | 0.00915 | 0.4775
2942004 | 지상 3층 | 지상 3층 | 2940510 | 915 | 0.23875 | 0.00915 | 0.4775
2942005 | 지상 3층 | 지상 3층 | 2940510 | 915 | 0.23875 | 0.00915 | 0.4775
2942006 | 지상 3층 | 지상 3층 | 2940510 | 915 | 0.23875 | 0.00915 | 0.4775
2942007 | 지상 3층 | 지상 3층 | 2940510 | 915 | 0.23875 | 0.00915 | 0.4775
2942008 | 지상 3층 | 지상 3층 | 2940510 | 950 | 0.2475 | 0.0095 | 0.485
2942009 | 지상 3층 | 지상 3층 | 2940510 | 600 | 0.16 | 0.006 | 0.3
2942010 | 지상 3층 | 지상 3층 | 2940510 | 1070 | 0.2775 | 0.0107 | 0.535
2942011 | 지상 3층 | 지상 3층 | 2940510 | 1480 | 0.38 | 0.0148 | 0.75
2942048 | 지상 3층 | 지상 3층 | 2940510 | 915 | 0.23875 | 0.00915 | 0.4775
2942049 | 지상 3층 | 지상 3층 | 2940510 | 915 | 0.23875 | 0.00915 | 0.4775
2942050 | 지상 3층 | 지상 3층 | 2940510 | 915 | 0.23875 | 0.00915 | 0.4775
2942051 | 지상 3층 | 지상 3층 | 2940510 | 915 | 0.23875 | 0.00915 | 0.4775
2942052 | 지상 3층 | 지상 3층 | 2940510 | 915 | 0.23875 | 0.00915 | 0.4775
2942053 | 지상 3층 | 지상 3층 | 2940510 | 950 | 0.2475 | 0.0095 | 0.485
2942054 | 지상 3층 | 지상 3층 | 2940510 | 600 | 0.16 | 0.006 | 0.3
2942055 | 지상 3층 | 지상 3층 | 2940510 | 1070 | 0.2775 | 0.0107 | 0.535
2942056 | 지상 3층 | 지상 3층 | 2940510 | 1480 | 0.38 | 0.0148 | 0.75
2942093 | 지상 3층 | 지상 3층 | 2940510 | 915 | 0.23875 | 0.00915 | 0.4775
2942094 | 지상 3층 | 지상 3층 | 2940510 | 915 | 0.23875 | 0.00915 | 0.4775
2942095 | 지상 3층 | 지상 3층 | 2940510 | 915 | 0.23875 | 0.00915 | 0.4775
2942096 | 지상 3층 | 지상 3층 | 2940510 | 915 | 0.23875 | 0.00915 | 0.4775
2942097 | 지상 3층 | 지상 3층 | 2940510 | 915 | 0.23875 | 0.00915 | 0.4775
2942098 | 지상 3층 | 지상 3층 | 2940510 | 950 | 0.2475 | 0.0095 | 0.485
2942099 | 지상 3층 | 지상 3층 | 2940510 | 600 | 0.16 | 0.006 | 0.3
2942100 | 지상 3층 | 지상 3층 | 2940510 | 1070 | 0.2775 | 0.0107 | 0.535
2942101 | 지상 3층 | 지상 3층 | 2940510 | 1480 | 0.38 | 0.0148 | 0.75
2942138 | 지상 3층 | 지상 3층 | 2940510 | 915 | 0.23875 | 0.00915 | 0.4775
2942139 | 지상 3층 | 지상 3층 | 2940510 | 915 | 0.23875 | 0.00915 | 0.4775
2942140 | 지상 3층 | 지상 3층 | 2940510 | 915 | 0.23875 | 0.00915 | 0.4775
2942141 | 지상 3층 | 지상 3층 | 2940510 | 915 | 0.23875 | 0.00915 | 0.4775
2942142 | 지상 3층 | 지상 3층 | 2940510 | 915 | 0.23875 | 0.00915 | 0.4775
2942143 | 지상 3층 | 지상 3층 | 2940510 | 950 | 0.2475 | 0.0095 | 0.485
2942144 | 지상 3층 | 지상 3층 | 2940510 | 600 | 0.16 | 0.006 | 0.3
2942145 | 지상 3층 | 지상 3층 | 2940510 | 1070 | 0.2775 | 0.0107 | 0.535
2942146 | 지상 3층 | 지상 3층 | 2940510 | 1480 | 0.38 | 0.0148 | 0.75
2942178 | 지상 3층 | 지상 3층 | 2940510 | 915 | 0.23875 | 0.00915 | 0.4775
2942179 | 지상 3층 | 지상 3층 | 2940510 | 915 | 0.23875 | 0.00915 | 0.4775
2942180 | 지상 3층 | 지상 3층 | 2940510 | 915 | 0.23875 | 0.00915 | 0.4775
2942181 | 지상 3층 | 지상 3층 | 2940510 | 915 | 0.23875 | 0.00915 | 0.4775
2942182 | 지상 3층 | 지상 3층 | 2940510 | 915 | 0.23875 | 0.00915 | 0.4775
2942183 | 지상 3층 | 지상 3층 | 2940510 | 950 | 0.2475 | 0.0095 | 0.485
2942184 | 지상 3층 | 지상 3층 | 2940510 | 600 | 0.16 | 0.006 | 0.3
2942185 | 지상 3층 | 지상 3층 | 2940510 | 1070 | 0.2775 | 0.0107 | 0.535
2942186 | 지상 3층 | 지상 3층 | 2940510 | 1480 | 0.38 | 0.0148 | 0.75
2942349 | 지상 3층 | 지상 3층 | 2940510 | 915 | 0.23875 | 0.00915 | 0.4775
2942350 | 지상 3층 | 지상 3층 | 2940510 | 915 | 0.23875 | 0.00915 | 0.4775
2942351 | 지상 3층 | 지상 3층 | 2940510 | 915 | 0.23875 | 0.00915 | 0.4775
2942352 | 지상 3층 | 지상 3층 | 2940510 | 915 | 0.23875 | 0.00915 | 0.4775
2942353 | 지상 3층 | 지상 3층 | 2940510 | 915 | 0.23875 | 0.00915 | 0.4775
2942354 | 지상 3층 | 지상 3층 | 2940510 | 950 | 0.2475 | 0.0095 | 0.485
2942355 | 지상 3층 | 지상 3층 | 2940510 | 600 | 0.16 | 0.006 | 0.3
2942356 | 지상 3층 | 지상 3층 | 2940510 | 1070 | 0.2775 | 0.0107 | 0.535
2942357 | 지상 3층 | 지상 3층 | 2940510 | 1480 | 0.38 | 0.0148 | 0.75
2942394 | 지상 3층 | 지상 3층 | 2940510 | 915 | 0.23875 | 0.00915 | 0.4775
2942395 | 지상 3층 | 지상 3층 | 2940510 | 915 | 0.23875 | 0.00915 | 0.4775
2942396 | 지상 3층 | 지상 3층 | 2940510 | 915 | 0.23875 | 0.00915 | 0.4775
2942397 | 지상 3층 | 지상 3층 | 2940510 | 915 | 0.23875 | 0.00915 | 0.4775
2942398 | 지상 3층 | 지상 3층 | 2940510 | 915 | 0.23875 | 0.00915 | 0.4775
2942399 | 지상 3층 | 지상 3층 | 2940510 | 950 | 0.2475 | 0.0095 | 0.485
2942400 | 지상 3층 | 지상 3층 | 2940510 | 600 | 0.16 | 0.006 | 0.3
2942401 | 지상 3층 | 지상 3층 | 2940510 | 1070 | 0.2775 | 0.0107 | 0.535
2942402 | 지상 3층 | 지상 3층 | 2940510 | 1480 | 0.38 | 0.0148 | 0.75
2942673 | 지상 3층 | 지상 3층 | 2940510 | 915 | 0.23875 | 0.00915 | 0.4775
2942674 | 지상 3층 | 지상 3층 | 2940510 | 945 | 0.24625 | 0.00945 | 0.4925
2942675 | 지상 3층 | 지상 3층 | 2940510 | 945 | 0.24625 | 0.00945 | 0.4925
2942676 | 지상 3층 | 지상 3층 | 2940510 | 945 | 0.24625 | 0.00945 | 0.4925
2942677 | 지상 3층 | 지상 3층 | 2940510 | 945 | 0.24625 | 0.00945 | 0.4925
2942678 | 지상 3층 | 지상 3층 | 2940510 | 950 | 0.2475 | 0.0095 | 0.485
2942679 | 지상 3층 | 지상 3층 | 2940510 | 600 | 0.16 | 0.006 | 0.3
2942680 | 지상 3층 | 지상 3층 | 2940510 | 1070 | 0.2775 | 0.0107 | 0.535
2942681 | 지상 3층 | 지상 3층 | 2940510 | 1480 | 0.38 | 0.0148 | 0.75
2942718 | 지상 3층 | 지상 3층 | 2940510 | 945 | 0.24625 | 0.00945 | 0.4925
2942719 | 지상 3층 | 지상 3층 | 2940510 | 1010 | 0.2625 | 0.0101 | 0.525
2942720 | 지상 3층 | 지상 3층 | 2940510 | 1010 | 0.2625 | 0.0101 | 0.525
2942721 | 지상 3층 | 지상 3층 | 2940510 | 1010 | 0.2625 | 0.0101 | 0.525
2942722 | 지상 3층 | 지상 3층 | 2940510 | 1010 | 0.2625 | 0.0101 | 0.525
2942723 | 지상 3층 | 지상 3층 | 2940510 | 950 | 0.2475 | 0.0095 | 0.485
2942724 | 지상 3층 | 지상 3층 | 2940510 | 600 | 0.16 | 0.006 | 0.3
2942725 | 지상 3층 | 지상 3층 | 2940510 | 1070 | 0.2775 | 0.0107 | 0.535
2942726 | 지상 3층 | 지상 3층 | 2940510 | 1480 | 0.38 | 0.0148 | 0.75
2943043 | 지상 3층 | 지상 3층 | 2940510 | 1010 | 0.2625 | 0.0101 | 0.525
2943044 | 지상 3층 | 지상 3층 | 2940510 | 1070 | 0.2775 | 0.0107 | 0.555
2943045 | 지상 3층 | 지상 3층 | 2940510 | 1070 | 0.2775 | 0.0107 | 0.555
2943046 | 지상 3층 | 지상 3층 | 2940510 | 1010 | 0.2625 | 0.0101 | 0.525
2943047 | 지상 3층 | 지상 3층 | 2940510 | 915 | 0.23875 | 0.00915 | 0.4775
2943048 | 지상 3층 | 지상 3층 | 2940510 | 915 | 0.23875 | 0.00915 | 0.4775
2943049 | 지상 3층 | 지상 3층 | 2940510 | 915 | 0.23875 | 0.00915 | 0.4775
2943050 | 지상 3층 | 지상 3층 | 2940510 | 915 | 0.23875 | 0.00915 | 0.4775
2943051 | 지상 3층 | 지상 3층 | 2940510 | 915 | 0.23875 | 0.00915 | 0.4775
2943052 | 지상 3층 | 지상 3층 | 2940510 | 915 | 0.23875 | 0.00915 | 0.4775
2943053 | 지상 3층 | 지상 3층 | 2940510 | 915 | 0.23875 | 0.00915 | 0.4775
2943054 | 지상 3층 | 지상 3층 | 2940510 | 915 | 0.23875 | 0.00915 | 0.4775
2943055 | 지상 3층 | 지상 3층 | 2940510 | 915 | 0.23875 | 0.00915 | 0.4775
2943056 | 지상 3층 | 지상 3층 | 2940510 | 1070 | 0.2775 | 0.0107 | 0.555
2943057 | 지상 3층 | 지상 3층 | 2940510 | 1070 | 0.2775 | 0.0107 | 0.555
2943058 | 지상 3층 | 지상 3층 | 2940510 | 1010 | 0.2625 | 0.0101 | 0.525
2943059 | 지상 3층 | 지상 3층 | 2940510 | 915 | 0.23875 | 0.00915 | 0.4775
2943060 | 지상 3층 | 지상 3층 | 2940510 | 915 | 0.23875 | 0.00915 | 0.4775
2943061 | 지상 3층 | 지상 3층 | 2940510 | 915 | 0.23875 | 0.00915 | 0.4775
2943062 | 지상 3층 | 지상 3층 | 2940510 | 915 | 0.23875 | 0.00915 | 0.4775
2943063 | 지상 3층 | 지상 3층 | 2940510 | 915 | 0.23875 | 0.00915 | 0.4775
2943064 | 지상 3층 | 지상 3층 | 2940510 | 915 | 0.23875 | 0.00915 | 0.4775
2943065 | 지상 3층 | 지상 3층 | 2940510 | 915 | 0.23875 | 0.00915 | 0.4775
2943066 | 지상 3층 | 지상 3층 | 2940510 | 915 | 0.23875 | 0.00915 | 0.4775
2943067 | 지상 3층 | 지상 3층 | 2940510 | 915 | 0.23875 | 0.00915 | 0.4775
2943068 | 지상 3층 | 지상 3층 | 2940510 | 910 | 0.2375 | 0.0091 | 0.475
2943069 | 지상 3층 | 지상 3층 | 2940510 | 1070 | 0.2775 | 0.0107 | 0.555
2943070 | 지상 3층 | 지상 3층 | 2940510 | 1070 | 0.2775 | 0.0107 | 0.555
2943071 | 지상 3층 | 지상 3층 | 2940510 | 1010 | 0.2625 | 0.0101 | 0.525
2943072 | 지상 3층 | 지상 3층 | 2940510 | 915 | 0.23875 | 0.00915 | 0.4775
2943073 | 지상 3층 | 지상 3층 | 2940510 | 915 | 0.23875 | 0.00915 | 0.4775
2943074 | 지상 3층 | 지상 3층 | 2940510 | 915 | 0.23875 | 0.00915 | 0.4775
2943075 | 지상 3층 | 지상 3층 | 2940510 | 915 | 0.23875 | 0.00915 | 0.4775
2943076 | 지상 3층 | 지상 3층 | 2940510 | 915 | 0.23875 | 0.00915 | 0.4775
2943077 | 지상 3층 | 지상 3층 | 2940510 | 915 | 0.23875 | 0.00915 | 0.4775
2943078 | 지상 3층 | 지상 3층 | 2940510 | 915 | 0.23875 | 0.00915 | 0.4775
2943079 | 지상 3층 | 지상 3층 | 2940510 | 915 | 0.23875 | 0.00915 | 0.4775
2943080 | 지상 3층 | 지상 3층 | 2940510 | 915 | 0.23875 | 0.00915 | 0.4775
2943081 | 지상 3층 | 지상 3층 | 2940510 | 910 | 0.2375 | 0.0091 | 0.475
2943082 | 지상 3층 | 지상 3층 | 2940510 | 1070 | 0.2775 | 0.0107 | 0.555
2943083 | 지상 3층 | 지상 3층 | 2940510 | 1070 | 0.2775 | 0.0107 | 0.555
2943084 | 지상 3층 | 지상 3층 | 2940510 | 1010 | 0.2625 | 0.0101 | 0.525
2943085 | 지상 3층 | 지상 3층 | 2940510 | 915 | 0.23875 | 0.00915 | 0.4775
2943086 | 지상 3층 | 지상 3층 | 2940510 | 915 | 0.23875 | 0.00915 | 0.4775
2943087 | 지상 3층 | 지상 3층 | 2940510 | 915 | 0.23875 | 0.00915 | 0.4775
2943088 | 지상 3층 | 지상 3층 | 2940510 | 915 | 0.23875 | 0.00915 | 0.4775
2943089 | 지상 3층 | 지상 3층 | 2940510 | 915 | 0.23875 | 0.00915 | 0.4775
2943090 | 지상 3층 | 지상 3층 | 2940510 | 915 | 0.23875 | 0.00915 | 0.4775
2943091 | 지상 3층 | 지상 3층 | 2940510 | 915 | 0.23875 | 0.00915 | 0.4775
2943092 | 지상 3층 | 지상 3층 | 2940510 | 915 | 0.23875 | 0.00915 | 0.4775
2943093 | 지상 3층 | 지상 3층 | 2940510 | 915 | 0.23875 | 0.00915 | 0.4775
2943094 | 지상 3층 | 지상 3층 | 2940510 | 910 | 0.2375 | 0.0091 | 0.475
2943095 | 지상 3층 | 지상 3층 | 2940510 | 1070 | 0.2775 | 0.0107 | 0.555
2943096 | 지상 3층 | 지상 3층 | 2940510 | 1070 | 0.2775 | 0.0107 | 0.555
2943097 | 지상 3층 | 지상 3층 | 2940510 | 1010 | 0.2625 | 0.0101 | 0.525
2943098 | 지상 3층 | 지상 3층 | 2940510 | 915 | 0.23875 | 0.00915 | 0.4775
2943099 | 지상 3층 | 지상 3층 | 2940510 | 915 | 0.23875 | 0.00915 | 0.4775
2943100 | 지상 3층 | 지상 3층 | 2940510 | 915 | 0.23875 | 0.00915 | 0.4775
2943101 | 지상 3층 | 지상 3층 | 2940510 | 915 | 0.23875 | 0.00915 | 0.4775
2943102 | 지상 3층 | 지상 3층 | 2940510 | 915 | 0.23875 | 0.00915 | 0.4775
2943103 | 지상 3층 | 지상 3층 | 2940510 | 915 | 0.23875 | 0.00915 | 0.4775
2943104 | 지상 3층 | 지상 3층 | 2940510 | 915 | 0.23875 | 0.00915 | 0.4775
2943105 | 지상 3층 | 지상 3층 | 2940510 | 915 | 0.23875 | 0.00915 | 0.4775
2943106 | 지상 3층 | 지상 3층 | 2940510 | 915 | 0.23875 | 0.00915 | 0.4775
2943107 | 지상 3층 | 지상 3층 | 2940510 | 910 | 0.2375 | 0.0091 | 0.475
2943108 | 지상 3층 | 지상 3층 | 2940510 | 950 | 0.2475 | 0.0095 | 0.485
2943109 | 지상 3층 | 지상 3층 | 2940510 | 950 | 0.2475 | 0.0095 | 0.485
2943110 | 지상 3층 | 지상 3층 | 2940510 | 950 | 0.2475 | 0.0095 | 0.485
2943111 | 지상 3층 | 지상 3층 | 2940510 | 950 | 0.2475 | 0.0095 | 0.485
2943112 | 지상 3층 | 지상 3층 | 2940510 | 950 | 0.2475 | 0.0095 | 0.485
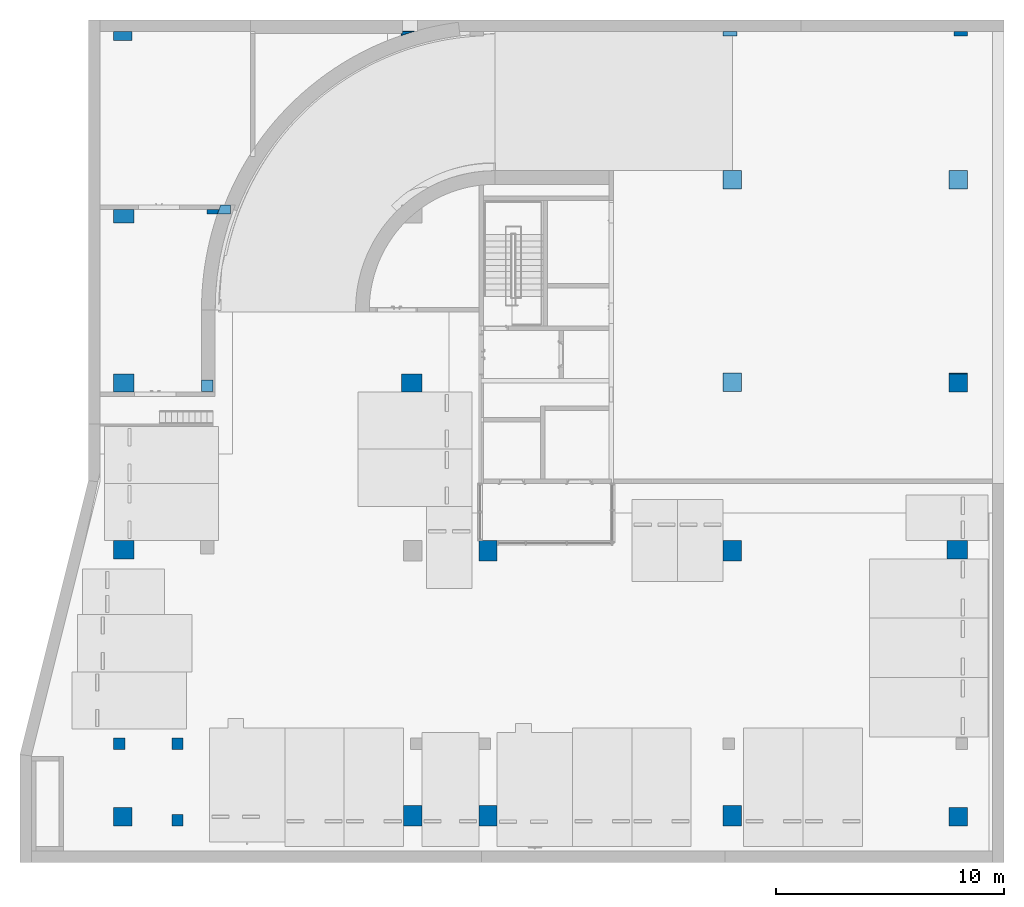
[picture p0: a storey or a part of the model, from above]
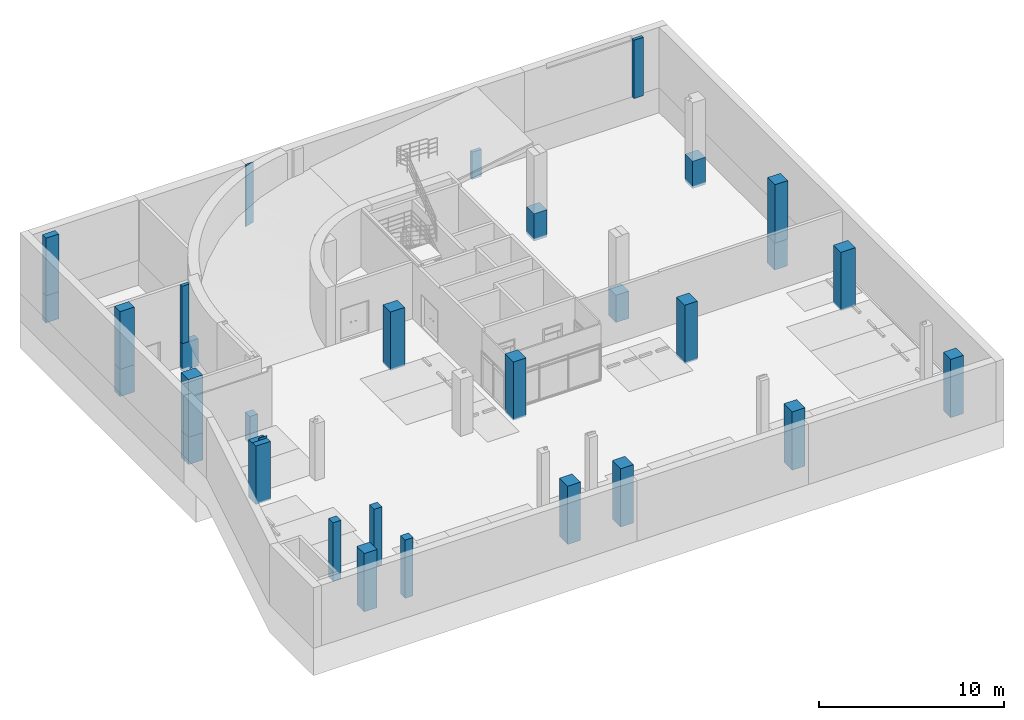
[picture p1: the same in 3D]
Properties of the parts of a building model (IFC2X3), part 17 of 39

# IfcMember: 직사각형 멀리언:CW200-직사각형 멀리언 50x200mm (8700)
Name (직사각형 멀리언:CW200-직사각형 멀리언 50x200mm:...) | In | 레벨 | 호스트 ID | 길이 (mm) = Span (mm) | 면적 (m2) = CrossSectionArea (m2) | 체적 (m3) = NetVolume (m3) | NetSurfaceArea (m2)
2943113 | 지상 3층 | 지상 3층 | 2940510 | 950 | 0.2475 | 0.0095 | 0.485
2943114 | 지상 3층 | 지상 3층 | 2940510 | 950 | 0.2475 | 0.0095 | 0.485
2943115 | 지상 3층 | 지상 3층 | 2940510 | 950 | 0.2475 | 0.0095 | 0.485
2943116 | 지상 3층 | 지상 3층 | 2940510 | 950 | 0.2475 | 0.0095 | 0.485
2943117 | 지상 3층 | 지상 3층 | 2940510 | 950 | 0.2475 | 0.0095 | 0.485
2943118 | 지상 3층 | 지상 3층 | 2940510 | 950 | 0.2475 | 0.0095 | 0.485
2943119 | 지상 3층 | 지상 3층 | 2940510 | 950 | 0.2475 | 0.0095 | 0.485
2943120 | 지상 3층 | 지상 3층 | 2940510 | 950 | 0.2475 | 0.0095 | 0.485
2943121 | 지상 3층 | 지상 3층 | 2940510 | 600 | 0.16 | 0.006 | 0.3
2943122 | 지상 3층 | 지상 3층 | 2940510 | 600 | 0.16 | 0.006 | 0.3
2943123 | 지상 3층 | 지상 3층 | 2940510 | 600 | 0.16 | 0.006 | 0.3
2943124 | 지상 3층 | 지상 3층 | 2940510 | 600 | 0.16 | 0.006 | 0.3
2943125 | 지상 3층 | 지상 3층 | 2940510 | 600 | 0.16 | 0.006 | 0.3
2943126 | 지상 3층 | 지상 3층 | 2940510 | 600 | 0.16 | 0.006 | 0.3
2943127 | 지상 3층 | 지상 3층 | 2940510 | 600 | 0.16 | 0.006 | 0.3
2943128 | 지상 3층 | 지상 3층 | 2940510 | 600 | 0.16 | 0.006 | 0.3
2943129 | 지상 3층 | 지상 3층 | 2940510 | 600 | 0.16 | 0.006 | 0.3
2943130 | 지상 3층 | 지상 3층 | 2940510 | 600 | 0.16 | 0.006 | 0.3
2943131 | 지상 3층 | 지상 3층 | 2940510 | 600 | 0.16 | 0.006 | 0.3
2943132 | 지상 3층 | 지상 3층 | 2940510 | 600 | 0.16 | 0.006 | 0.3
2943133 | 지상 3층 | 지상 3층 | 2940510 | 600 | 0.16 | 0.006 | 0.3
2943134 | 지상 3층 | 지상 3층 | 2940510 | 1070 | 0.2775 | 0.0107 | 0.535
2943135 | 지상 3층 | 지상 3층 | 2940510 | 1070 | 0.2775 | 0.0107 | 0.535
2943136 | 지상 3층 | 지상 3층 | 2940510 | 1070 | 0.2775 | 0.0107 | 0.535
2943137 | 지상 3층 | 지상 3층 | 2940510 | 1070 | 0.2775 | 0.0107 | 0.535
2943138 | 지상 3층 | 지상 3층 | 2940510 | 1070 | 0.2775 | 0.0107 | 0.535
2943139 | 지상 3층 | 지상 3층 | 2940510 | 1070 | 0.2775 | 0.0107 | 0.535
2943140 | 지상 3층 | 지상 3층 | 2940510 | 1070 | 0.2775 | 0.0107 | 0.535
2943141 | 지상 3층 | 지상 3층 | 2940510 | 1070 | 0.2775 | 0.0107 | 0.535
2943142 | 지상 3층 | 지상 3층 | 2940510 | 1070 | 0.2775 | 0.0107 | 0.535
2943143 | 지상 3층 | 지상 3층 | 2940510 | 1070 | 0.2775 | 0.0107 | 0.535
2943144 | 지상 3층 | 지상 3층 | 2940510 | 1070 | 0.2775 | 0.0107 | 0.535
2943145 | 지상 3층 | 지상 3층 | 2940510 | 1070 | 0.2775 | 0.0107 | 0.535
2943146 | 지상 3층 | 지상 3층 | 2940510 | 1070 | 0.2775 | 0.0107 | 0.535
2943147 | 지상 3층 | 지상 3층 | 2940510 | 1480 | 0.38 | 0.0148 | 0.75
2943148 | 지상 3층 | 지상 3층 | 2940510 | 1480 | 0.38 | 0.0148 | 0.75
2943149 | 지상 3층 | 지상 3층 | 2940510 | 1480 | 0.38 | 0.0148 | 0.75
2943150 | 지상 3층 | 지상 3층 | 2940510 | 1480 | 0.38 | 0.0148 | 0.75
2943151 | 지상 3층 | 지상 3층 | 2940510 | 1480 | 0.38 | 0.0148 | 0.75
2943152 | 지상 3층 | 지상 3층 | 2940510 | 1480 | 0.38 | 0.0148 | 0.75
2943153 | 지상 3층 | 지상 3층 | 2940510 | 1480 | 0.38 | 0.0148 | 0.75
2943154 | 지상 3층 | 지상 3층 | 2940510 | 1480 | 0.38 | 0.0148 | 0.75
2943155 | 지상 3층 | 지상 3층 | 2940510 | 1480 | 0.38 | 0.0148 | 0.75
2943156 | 지상 3층 | 지상 3층 | 2940510 | 1480 | 0.38 | 0.0148 | 0.75
2943157 | 지상 3층 | 지상 3층 | 2940510 | 1480 | 0.38 | 0.0148 | 0.75
2943158 | 지상 3층 | 지상 3층 | 2940510 | 1480 | 0.38 | 0.0148 | 0.75
2943159 | 지상 3층 | 지상 3층 | 2940510 | 1480 | 0.38 | 0.0148 | 0.75
2943263 | 지상 3층 | 지상 3층 | 2940510 | 1010 | 0.2625 | 0.0101 | 0.525
2943264 | 지상 3층 | 지상 3층 | 2940510 | 970 | 0.2525 | 0.0097 | 0.505
2943265 | 지상 3층 | 지상 3층 | 2940510 | 915 | 0.23875 | 0.00915 | 0.4775
2943266 | 지상 3층 | 지상 3층 | 2940510 | 915 | 0.23875 | 0.00915 | 0.4775
2943267 | 지상 3층 | 지상 3층 | 2940510 | 915 | 0.23875 | 0.00915 | 0.4775
2943268 | 지상 3층 | 지상 3층 | 2940510 | 915 | 0.23875 | 0.00915 | 0.4775
2943269 | 지상 3층 | 지상 3층 | 2940510 | 915 | 0.23875 | 0.00915 | 0.4775
2943270 | 지상 3층 | 지상 3층 | 2940510 | 915 | 0.23875 | 0.00915 | 0.4775
2943271 | 지상 3층 | 지상 3층 | 2940510 | 915 | 0.23875 | 0.00915 | 0.4775
2943272 | 지상 3층 | 지상 3층 | 2940510 | 1015 | 0.26375 | 0.01015 | 0.5275
2943274 | 지상 3층 | 지상 3층 | 2940510 | 970 | 0.2525 | 0.0097 | 0.505
2943275 | 지상 3층 | 지상 3층 | 2940510 | 915 | 0.23875 | 0.00915 | 0.4775
2943276 | 지상 3층 | 지상 3층 | 2940510 | 915 | 0.23875 | 0.00915 | 0.4775
2943277 | 지상 3층 | 지상 3층 | 2940510 | 915 | 0.23875 | 0.00915 | 0.4775
2943278 | 지상 3층 | 지상 3층 | 2940510 | 915 | 0.23875 | 0.00915 | 0.4775
2943279 | 지상 3층 | 지상 3층 | 2940510 | 915 | 0.23875 | 0.00915 | 0.4775
2943280 | 지상 3층 | 지상 3층 | 2940510 | 915 | 0.23875 | 0.00915 | 0.4775
2943281 | 지상 3층 | 지상 3층 | 2940510 | 915 | 0.23875 | 0.00915 | 0.4775
2943282 | 지상 3층 | 지상 3층 | 2940510 | 1015 | 0.26375 | 0.01015 | 0.5275
2943283 | 지상 3층 | 지상 3층 | 2940510 | 892.808 | 0.233202 | 0.00892808 | 0.466404
2943285 | 지상 3층 | 지상 3층 | 2940510 | 970 | 0.2525 | 0.0097 | 0.505
2943286 | 지상 3층 | 지상 3층 | 2940510 | 915 | 0.23875 | 0.00915 | 0.4775
2943287 | 지상 3층 | 지상 3층 | 2940510 | 915 | 0.23875 | 0.00915 | 0.4775
2943288 | 지상 3층 | 지상 3층 | 2940510 | 915 | 0.23875 | 0.00915 | 0.4775
2943289 | 지상 3층 | 지상 3층 | 2940510 | 915 | 0.23875 | 0.00915 | 0.4775
2943290 | 지상 3층 | 지상 3층 | 2940510 | 915 | 0.23875 | 0.00915 | 0.4775
2943291 | 지상 3층 | 지상 3층 | 2940510 | 915 | 0.23875 | 0.00915 | 0.4775
2943292 | 지상 3층 | 지상 3층 | 2940510 | 915 | 0.23875 | 0.00915 | 0.4775
2943293 | 지상 3층 | 지상 3층 | 2940510 | 1015 | 0.26375 | 0.01015 | 0.5275
2943294 | 지상 3층 | 지상 3층 | 2940510 | 892.808 | 0.233202 | 0.00892808 | 0.466404
2943296 | 지상 3층 | 지상 3층 | 2940510 | 970 | 0.2525 | 0.0097 | 0.505
2943297 | 지상 3층 | 지상 3층 | 2940510 | 915 | 0.23875 | 0.00915 | 0.4775
2943298 | 지상 3층 | 지상 3층 | 2940510 | 915 | 0.23875 | 0.00915 | 0.4775
2943299 | 지상 3층 | 지상 3층 | 2940510 | 915 | 0.23875 | 0.00915 | 0.4775
2943300 | 지상 3층 | 지상 3층 | 2940510 | 915 | 0.23875 | 0.00915 | 0.4775
2943301 | 지상 3층 | 지상 3층 | 2940510 | 915 | 0.23875 | 0.00915 | 0.4775
2943302 | 지상 3층 | 지상 3층 | 2940510 | 915 | 0.23875 | 0.00915 | 0.4775
2943303 | 지상 3층 | 지상 3층 | 2940510 | 915 | 0.23875 | 0.00915 | 0.4775
2943304 | 지상 3층 | 지상 3층 | 2940510 | 1015 | 0.26375 | 0.01015 | 0.5275
2943305 | 지상 3층 | 지상 3층 | 2940510 | 892.808 | 0.233202 | 0.00892808 | 0.466404
2943307 | 지상 3층 | 지상 3층 | 2940510 | 970 | 0.2525 | 0.0097 | 0.505
2943308 | 지상 3층 | 지상 3층 | 2940510 | 915 | 0.23875 | 0.00915 | 0.4775
2943309 | 지상 3층 | 지상 3층 | 2940510 | 915 | 0.23875 | 0.00915 | 0.4775
2943310 | 지상 3층 | 지상 3층 | 2940510 | 915 | 0.23875 | 0.00915 | 0.4775
2943311 | 지상 3층 | 지상 3층 | 2940510 | 915 | 0.23875 | 0.00915 | 0.4775
2943312 | 지상 3층 | 지상 3층 | 2940510 | 915 | 0.23875 | 0.00915 | 0.4775
2943313 | 지상 3층 | 지상 3층 | 2940510 | 915 | 0.23875 | 0.00915 | 0.4775
2943314 | 지상 3층 | 지상 3층 | 2940510 | 915 | 0.23875 | 0.00915 | 0.4775
2943315 | 지상 3층 | 지상 3층 | 2940510 | 1015 | 0.26375 | 0.01015 | 0.5275
2943316 | 지상 3층 | 지상 3층 | 2940510 | 892.808 | 0.233202 | 0.00892808 | 0.466404
2943318 | 지상 3층 | 지상 3층 | 2940510 | 950 | 0.2475 | 0.0095 | 0.485
2943319 | 지상 3층 | 지상 3층 | 2940510 | 950 | 0.2475 | 0.0095 | 0.485
2943320 | 지상 3층 | 지상 3층 | 2940510 | 950 | 0.2475 | 0.0095 | 0.485
2943321 | 지상 3층 | 지상 3층 | 2940510 | 950 | 0.2475 | 0.0095 | 0.485
2943322 | 지상 3층 | 지상 3층 | 2940510 | 950 | 0.2475 | 0.0095 | 0.485
2943323 | 지상 3층 | 지상 3층 | 2940510 | 950 | 0.2475 | 0.0095 | 0.485
2943324 | 지상 3층 | 지상 3층 | 2940510 | 950 | 0.2475 | 0.0095 | 0.485
2943325 | 지상 3층 | 지상 3층 | 2940510 | 950 | 0.2475 | 0.0095 | 0.485
2943326 | 지상 3층 | 지상 3층 | 2940510 | 950 | 0.2475 | 0.0095 | 0.485
2943327 | 지상 3층 | 지상 3층 | 2940510 | 950 | 0.2475 | 0.0095 | 0.485
2943329 | 지상 3층 | 지상 3층 | 2940510 | 600 | 0.16 | 0.006 | 0.3
2943330 | 지상 3층 | 지상 3층 | 2940510 | 600 | 0.16 | 0.006 | 0.3
2943331 | 지상 3층 | 지상 3층 | 2940510 | 600 | 0.16 | 0.006 | 0.3
2943332 | 지상 3층 | 지상 3층 | 2940510 | 600 | 0.16 | 0.006 | 0.3
2943333 | 지상 3층 | 지상 3층 | 2940510 | 600 | 0.16 | 0.006 | 0.3
2943334 | 지상 3층 | 지상 3층 | 2940510 | 600 | 0.16 | 0.006 | 0.3
2943335 | 지상 3층 | 지상 3층 | 2940510 | 600 | 0.16 | 0.006 | 0.3
2943336 | 지상 3층 | 지상 3층 | 2940510 | 600 | 0.16 | 0.006 | 0.3
2943337 | 지상 3층 | 지상 3층 | 2940510 | 600 | 0.16 | 0.006 | 0.3
2943338 | 지상 3층 | 지상 3층 | 2940510 | 600 | 0.16 | 0.006 | 0.3
2943340 | 지상 3층 | 지상 3층 | 2940510 | 1070 | 0.2775 | 0.0107 | 0.535
2943341 | 지상 3층 | 지상 3층 | 2940510 | 1070 | 0.2775 | 0.0107 | 0.535
2943342 | 지상 3층 | 지상 3층 | 2940510 | 1070 | 0.2775 | 0.0107 | 0.535
2943343 | 지상 3층 | 지상 3층 | 2940510 | 1070 | 0.2775 | 0.0107 | 0.535
2943344 | 지상 3층 | 지상 3층 | 2940510 | 1070 | 0.2775 | 0.0107 | 0.535
2943345 | 지상 3층 | 지상 3층 | 2940510 | 1070 | 0.2775 | 0.0107 | 0.535
2943346 | 지상 3층 | 지상 3층 | 2940510 | 1070 | 0.2775 | 0.0107 | 0.535
2943347 | 지상 3층 | 지상 3층 | 2940510 | 1070 | 0.2775 | 0.0107 | 0.535
2943348 | 지상 3층 | 지상 3층 | 2940510 | 1070 | 0.2775 | 0.0107 | 0.535
2943349 | 지상 3층 | 지상 3층 | 2940510 | 1070 | 0.2775 | 0.0107 | 0.535
2943351 | 지상 3층 | 지상 3층 | 2940510 | 1480 | 0.38 | 0.0148 | 0.75
2943352 | 지상 3층 | 지상 3층 | 2940510 | 1480 | 0.38 | 0.0148 | 0.75
2943353 | 지상 3층 | 지상 3층 | 2940510 | 1480 | 0.38 | 0.0148 | 0.75
2943354 | 지상 3층 | 지상 3층 | 2940510 | 1480 | 0.38 | 0.0148 | 0.75
2943355 | 지상 3층 | 지상 3층 | 2940510 | 1480 | 0.38 | 0.0148 | 0.75
2943356 | 지상 3층 | 지상 3층 | 2940510 | 1480 | 0.38 | 0.0148 | 0.75
2943357 | 지상 3층 | 지상 3층 | 2940510 | 1480 | 0.38 | 0.0148 | 0.75
2943358 | 지상 3층 | 지상 3층 | 2940510 | 1480 | 0.38 | 0.0148 | 0.75
2943359 | 지상 3층 | 지상 3층 | 2940510 | 1480 | 0.38 | 0.0148 | 0.75
2943360 | 지상 3층 | 지상 3층 | 2940510 | 1480 | 0.38 | 0.0148 | 0.75
2943749 | 지상 3층 | 지상 3층 | 2940510 | 1010 | 0.2625 | 0.0101 | 0.525
2943750 | 지상 3층 | 지상 3층 | 2940510 | 1010 | 0.2625 | 0.0101 | 0.525
2943751 | 지상 3층 | 지상 3층 | 2940510 | 1010 | 0.2625 | 0.0101 | 0.525
2943752 | 지상 3층 | 지상 3층 | 2940510 | 1010 | 0.2625 | 0.0101 | 0.525
2943753 | 지상 3층 | 지상 3층 | 2940510 | 910 | 0.2375 | 0.0091 | 0.475
2943754 | 지상 3층 | 지상 3층 | 2940510 | 950 | 0.2475 | 0.0095 | 0.485
2943755 | 지상 3층 | 지상 3층 | 2940510 | 600 | 0.16 | 0.006 | 0.3
2943756 | 지상 3층 | 지상 3층 | 2940510 | 1070 | 0.2775 | 0.0107 | 0.535
2943757 | 지상 3층 | 지상 3층 | 2940510 | 1480 | 0.38 | 0.0148 | 0.75
2944602 | 지상 4층 | 지상 4층 | 2944600 | 892.808 | 0.233202 | 0.00892808 | 0.466404
2944608 | 지상 4층 | 지상 4층 | 2944600 | 912.816 | 0.238204 | 0.00912816 | 0.476408
2944610 | 지상 4층 | 지상 4층 | 2944600 | 920 | 0.24 | 0.0092 | 0.47
2944616 | 지상 4층 | 지상 4층 | 2944600 | 912.816 | 0.238204 | 0.00912816 | 0.476408
2944617 | 지상 4층 | 지상 4층 | 2944600 | 945 | 0.24625 | 0.00945 | 0.4925
2944618 | 지상 4층 | 지상 4층 | 2944600 | 600 | 0.16 | 0.006 | 0.3
2944624 | 지상 4층 | 지상 4층 | 2944600 | 912.816 | 0.238204 | 0.00912816 | 0.476408
2944625 | 지상 4층 | 지상 4층 | 2944600 | 945 | 0.24625 | 0.00945 | 0.4925
2944626 | 지상 4층 | 지상 4층 | 2944600 | 1100 | 0.285 | 0.011 | 0.56
2944640 | 지상 4층 | 지상 4층 | 2944600 | 945 | 0.24625 | 0.00945 | 0.4925
2944642 | 지상 4층 | 지상 4층 | 2944600 | 915 | 0.23875 | 0.00915 | 0.4775
2944643 | 지상 4층 | 지상 4층 | 2944600 | 915 | 0.23875 | 0.00915 | 0.4775
2944645 | 지상 4층 | 지상 4층 | 2944600 | 920 | 0.24 | 0.0092 | 0.47
2944646 | 지상 4층 | 지상 4층 | 2944600 | 600 | 0.16 | 0.006 | 0.3
2944647 | 지상 4층 | 지상 4층 | 2944600 | 1100 | 0.285 | 0.011 | 0.56
2944654 | 지상 4층 | 지상 4층 | 2944600 | 915 | 0.23875 | 0.00915 | 0.4775
2944656 | 지상 4층 | 지상 4층 | 2944600 | 915 | 0.23875 | 0.00915 | 0.4775
2944657 | 지상 4층 | 지상 4층 | 2944600 | 915 | 0.23875 | 0.00915 | 0.4775
2944659 | 지상 4층 | 지상 4층 | 2944600 | 920 | 0.24 | 0.0092 | 0.47
2944660 | 지상 4층 | 지상 4층 | 2944600 | 600 | 0.16 | 0.006 | 0.3
2944661 | 지상 4층 | 지상 4층 | 2944600 | 1100 | 0.285 | 0.011 | 0.56
2944668 | 지상 4층 | 지상 4층 | 2944600 | 915 | 0.23875 | 0.00915 | 0.4775
2944670 | 지상 4층 | 지상 4층 | 2944600 | 915 | 0.23875 | 0.00915 | 0.4775
2944671 | 지상 4층 | 지상 4층 | 2944600 | 915 | 0.23875 | 0.00915 | 0.4775
2944673 | 지상 4층 | 지상 4층 | 2944600 | 920 | 0.24 | 0.0092 | 0.47
2944674 | 지상 4층 | 지상 4층 | 2944600 | 600 | 0.16 | 0.006 | 0.3
2944675 | 지상 4층 | 지상 4층 | 2944600 | 1100 | 0.285 | 0.011 | 0.56
2944682 | 지상 4층 | 지상 4층 | 2944600 | 915 | 0.23875 | 0.00915 | 0.4775
2944684 | 지상 4층 | 지상 4층 | 2944600 | 915 | 0.23875 | 0.00915 | 0.4775
2944685 | 지상 4층 | 지상 4층 | 2944600 | 915 | 0.23875 | 0.00915 | 0.4775
2944687 | 지상 4층 | 지상 4층 | 2944600 | 920 | 0.24 | 0.0092 | 0.47
2944688 | 지상 4층 | 지상 4층 | 2944600 | 600 | 0.16 | 0.006 | 0.3
2944689 | 지상 4층 | 지상 4층 | 2944600 | 1100 | 0.285 | 0.011 | 0.56
2944696 | 지상 4층 | 지상 4층 | 2944600 | 915 | 0.23875 | 0.00915 | 0.4775
2944698 | 지상 4층 | 지상 4층 | 2944600 | 915 | 0.23875 | 0.00915 | 0.4775
2944699 | 지상 4층 | 지상 4층 | 2944600 | 915 | 0.23875 | 0.00915 | 0.4775
2944701 | 지상 4층 | 지상 4층 | 2944600 | 920 | 0.24 | 0.0092 | 0.47
2944702 | 지상 4층 | 지상 4층 | 2944600 | 600 | 0.16 | 0.006 | 0.3
2944703 | 지상 4층 | 지상 4층 | 2944600 | 1100 | 0.285 | 0.011 | 0.56
2944710 | 지상 4층 | 지상 4층 | 2944600 | 915 | 0.23875 | 0.00915 | 0.4775
2944712 | 지상 4층 | 지상 4층 | 2944600 | 915 | 0.23875 | 0.00915 | 0.4775
2944713 | 지상 4층 | 지상 4층 | 2944600 | 915 | 0.23875 | 0.00915 | 0.4775
2944715 | 지상 4층 | 지상 4층 | 2944600 | 920 | 0.24 | 0.0092 | 0.47
2944716 | 지상 4층 | 지상 4층 | 2944600 | 600 | 0.16 | 0.006 | 0.3
2944717 | 지상 4층 | 지상 4층 | 2944600 | 1100 | 0.285 | 0.011 | 0.56
2944724 | 지상 4층 | 지상 4층 | 2944600 | 915 | 0.23875 | 0.00915 | 0.4775
2944726 | 지상 4층 | 지상 4층 | 2944600 | 915 | 0.23875 | 0.00915 | 0.4775
2944727 | 지상 4층 | 지상 4층 | 2944600 | 915 | 0.23875 | 0.00915 | 0.4775
2944729 | 지상 4층 | 지상 4층 | 2944600 | 920 | 0.24 | 0.0092 | 0.47
2944730 | 지상 4층 | 지상 4층 | 2944600 | 600 | 0.16 | 0.006 | 0.3
2944731 | 지상 4층 | 지상 4층 | 2944600 | 1100 | 0.285 | 0.011 | 0.56
2944738 | 지상 4층 | 지상 4층 | 2944600 | 915 | 0.23875 | 0.00915 | 0.4775
2944740 | 지상 4층 | 지상 4층 | 2944600 | 915 | 0.23875 | 0.00915 | 0.4775
2944741 | 지상 4층 | 지상 4층 | 2944600 | 915 | 0.23875 | 0.00915 | 0.4775
2944743 | 지상 4층 | 지상 4층 | 2944600 | 920 | 0.24 | 0.0092 | 0.47
2944744 | 지상 4층 | 지상 4층 | 2944600 | 600 | 0.16 | 0.006 | 0.3
2944745 | 지상 4층 | 지상 4층 | 2944600 | 1100 | 0.285 | 0.011 | 0.56
2944752 | 지상 4층 | 지상 4층 | 2944600 | 915 | 0.23875 | 0.00915 | 0.4775
2944754 | 지상 4층 | 지상 4층 | 2944600 | 915 | 0.23875 | 0.00915 | 0.4775
2944755 | 지상 4층 | 지상 4층 | 2944600 | 915 | 0.23875 | 0.00915 | 0.4775
2944757 | 지상 4층 | 지상 4층 | 2944600 | 920 | 0.24 | 0.0092 | 0.47
2944758 | 지상 4층 | 지상 4층 | 2944600 | 600 | 0.16 | 0.006 | 0.3
2944759 | 지상 4층 | 지상 4층 | 2944600 | 1100 | 0.285 | 0.011 | 0.56
2944766 | 지상 4층 | 지상 4층 | 2944600 | 915 | 0.23875 | 0.00915 | 0.4775
2944768 | 지상 4층 | 지상 4층 | 2944600 | 915 | 0.23875 | 0.00915 | 0.4775
2944769 | 지상 4층 | 지상 4층 | 2944600 | 915 | 0.23875 | 0.00915 | 0.4775
2944771 | 지상 4층 | 지상 4층 | 2944600 | 920 | 0.24 | 0.0092 | 0.47
2944772 | 지상 4층 | 지상 4층 | 2944600 | 600 | 0.16 | 0.006 | 0.3
2944773 | 지상 4층 | 지상 4층 | 2944600 | 1100 | 0.285 | 0.011 | 0.56
2944780 | 지상 4층 | 지상 4층 | 2944600 | 915 | 0.23875 | 0.00915 | 0.4775
2944782 | 지상 4층 | 지상 4층 | 2944600 | 945 | 0.24625 | 0.00945 | 0.4925
2944783 | 지상 4층 | 지상 4층 | 2944600 | 945 | 0.24625 | 0.00945 | 0.4925
2944785 | 지상 4층 | 지상 4층 | 2944600 | 920 | 0.24 | 0.0092 | 0.47
2944786 | 지상 4층 | 지상 4층 | 2944600 | 600 | 0.16 | 0.006 | 0.3
2944787 | 지상 4층 | 지상 4층 | 2944600 | 1100 | 0.285 | 0.011 | 0.56
2944794 | 지상 4층 | 지상 4층 | 2944600 | 945 | 0.24625 | 0.00945 | 0.4925
2944796 | 지상 4층 | 지상 4층 | 2944600 | 1010 | 0.2625 | 0.0101 | 0.525
2944797 | 지상 4층 | 지상 4층 | 2944600 | 1010 | 0.2625 | 0.0101 | 0.525
2944799 | 지상 4층 | 지상 4층 | 2944600 | 920 | 0.24 | 0.0092 | 0.47
2944800 | 지상 4층 | 지상 4층 | 2944600 | 600 | 0.16 | 0.006 | 0.3
2944801 | 지상 4층 | 지상 4층 | 2944600 | 1100 | 0.285 | 0.011 | 0.56
2944868 | 지상 4층 | 지상 4층 | 2944600 | 1010 | 0.2625 | 0.0101 | 0.525
2944869 | 지상 4층 | 지상 4층 | 2944600 | 1070 | 0.2775 | 0.0107 | 0.555
2944870 | 지상 4층 | 지상 4층 | 2944600 | 1070 | 0.2775 | 0.0107 | 0.555
2944871 | 지상 4층 | 지상 4층 | 2944600 | 1010 | 0.2625 | 0.0101 | 0.525
2944872 | 지상 4층 | 지상 4층 | 2944600 | 915 | 0.23875 | 0.00915 | 0.4775
2944873 | 지상 4층 | 지상 4층 | 2944600 | 915 | 0.23875 | 0.00915 | 0.4775
2944874 | 지상 4층 | 지상 4층 | 2944600 | 915 | 0.23875 | 0.00915 | 0.4775
2944875 | 지상 4층 | 지상 4층 | 2944600 | 915 | 0.23875 | 0.00915 | 0.4775
2944876 | 지상 4층 | 지상 4층 | 2944600 | 915 | 0.23875 | 0.00915 | 0.4775
2944877 | 지상 4층 | 지상 4층 | 2944600 | 915 | 0.23875 | 0.00915 | 0.4775
2944878 | 지상 4층 | 지상 4층 | 2944600 | 915 | 0.23875 | 0.00915 | 0.4775
2944879 | 지상 4층 | 지상 4층 | 2944600 | 915 | 0.23875 | 0.00915 | 0.4775
2944880 | 지상 4층 | 지상 4층 | 2944600 | 915 | 0.23875 | 0.00915 | 0.4775
2944894 | 지상 4층 | 지상 4층 | 2944600 | 1070 | 0.2775 | 0.0107 | 0.555
2944895 | 지상 4층 | 지상 4층 | 2944600 | 1070 | 0.2775 | 0.0107 | 0.555
2944896 | 지상 4층 | 지상 4층 | 2944600 | 1010 | 0.2625 | 0.0101 | 0.525
2944897 | 지상 4층 | 지상 4층 | 2944600 | 915 | 0.23875 | 0.00915 | 0.4775
2944898 | 지상 4층 | 지상 4층 | 2944600 | 915 | 0.23875 | 0.00915 | 0.4775
2944899 | 지상 4층 | 지상 4층 | 2944600 | 915 | 0.23875 | 0.00915 | 0.4775
2944900 | 지상 4층 | 지상 4층 | 2944600 | 915 | 0.23875 | 0.00915 | 0.4775
2944901 | 지상 4층 | 지상 4층 | 2944600 | 915 | 0.23875 | 0.00915 | 0.4775
2944902 | 지상 4층 | 지상 4층 | 2944600 | 915 | 0.23875 | 0.00915 | 0.4775
2944903 | 지상 4층 | 지상 4층 | 2944600 | 915 | 0.23875 | 0.00915 | 0.4775
2944904 | 지상 4층 | 지상 4층 | 2944600 | 915 | 0.23875 | 0.00915 | 0.4775
2944905 | 지상 4층 | 지상 4층 | 2944600 | 915 | 0.23875 | 0.00915 | 0.4775
2944906 | 지상 4층 | 지상 4층 | 2944600 | 910 | 0.2375 | 0.0091 | 0.475
2944907 | 지상 4층 | 지상 4층 | 2944600 | 1070 | 0.2775 | 0.0107 | 0.555
2944908 | 지상 4층 | 지상 4층 | 2944600 | 1070 | 0.2775 | 0.0107 | 0.555
2944909 | 지상 4층 | 지상 4층 | 2944600 | 1010 | 0.2625 | 0.0101 | 0.525
2944910 | 지상 4층 | 지상 4층 | 2944600 | 915 | 0.23875 | 0.00915 | 0.4775
2944911 | 지상 4층 | 지상 4층 | 2944600 | 915 | 0.23875 | 0.00915 | 0.4775
2944912 | 지상 4층 | 지상 4층 | 2944600 | 915 | 0.23875 | 0.00915 | 0.4775
2944913 | 지상 4층 | 지상 4층 | 2944600 | 915 | 0.23875 | 0.00915 | 0.4775
2944914 | 지상 4층 | 지상 4층 | 2944600 | 915 | 0.23875 | 0.00915 | 0.4775
2944915 | 지상 4층 | 지상 4층 | 2944600 | 915 | 0.23875 | 0.00915 | 0.4775
2944916 | 지상 4층 | 지상 4층 | 2944600 | 915 | 0.23875 | 0.00915 | 0.4775
2944917 | 지상 4층 | 지상 4층 | 2944600 | 915 | 0.23875 | 0.00915 | 0.4775
2944918 | 지상 4층 | 지상 4층 | 2944600 | 915 | 0.23875 | 0.00915 | 0.4775
2944919 | 지상 4층 | 지상 4층 | 2944600 | 910 | 0.2375 | 0.0091 | 0.475
2944933 | 지상 4층 | 지상 4층 | 2944600 | 920 | 0.24 | 0.0092 | 0.47
2944934 | 지상 4층 | 지상 4층 | 2944600 | 920 | 0.24 | 0.0092 | 0.47
2944935 | 지상 4층 | 지상 4층 | 2944600 | 920 | 0.24 | 0.0092 | 0.47
2944936 | 지상 4층 | 지상 4층 | 2944600 | 920 | 0.24 | 0.0092 | 0.47
2944937 | 지상 4층 | 지상 4층 | 2944600 | 920 | 0.24 | 0.0092 | 0.47
2944938 | 지상 4층 | 지상 4층 | 2944600 | 920 | 0.24 | 0.0092 | 0.47
2944939 | 지상 4층 | 지상 4층 | 2944600 | 920 | 0.24 | 0.0092 | 0.47
2944940 | 지상 4층 | 지상 4층 | 2944600 | 920 | 0.24 | 0.0092 | 0.47
2944941 | 지상 4층 | 지상 4층 | 2944600 | 920 | 0.24 | 0.0092 | 0.47
2944942 | 지상 4층 | 지상 4층 | 2944600 | 920 | 0.24 | 0.0092 | 0.47
2944943 | 지상 4층 | 지상 4층 | 2944600 | 920 | 0.24 | 0.0092 | 0.47
2944944 | 지상 4층 | 지상 4층 | 2944600 | 920 | 0.24 | 0.0092 | 0.47
2944945 | 지상 4층 | 지상 4층 | 2944600 | 920 | 0.24 | 0.0092 | 0.47
2944946 | 지상 4층 | 지상 4층 | 2944600 | 600 | 0.16 | 0.006 | 0.3
2944947 | 지상 4층 | 지상 4층 | 2944600 | 600 | 0.16 | 0.006 | 0.3
2944948 | 지상 4층 | 지상 4층 | 2944600 | 600 | 0.16 | 0.006 | 0.3
2944949 | 지상 4층 | 지상 4층 | 2944600 | 600 | 0.16 | 0.006 | 0.3
2944950 | 지상 4층 | 지상 4층 | 2944600 | 600 | 0.16 | 0.006 | 0.3
2944951 | 지상 4층 | 지상 4층 | 2944600 | 600 | 0.16 | 0.006 | 0.3
2944952 | 지상 4층 | 지상 4층 | 2944600 | 600 | 0.16 | 0.006 | 0.3
2944953 | 지상 4층 | 지상 4층 | 2944600 | 600 | 0.16 | 0.006 | 0.3
2944954 | 지상 4층 | 지상 4층 | 2944600 | 600 | 0.16 | 0.006 | 0.3
2944955 | 지상 4층 | 지상 4층 | 2944600 | 600 | 0.16 | 0.006 | 0.3
2944956 | 지상 4층 | 지상 4층 | 2944600 | 600 | 0.16 | 0.006 | 0.3
2944957 | 지상 4층 | 지상 4층 | 2944600 | 600 | 0.16 | 0.006 | 0.3
2944958 | 지상 4층 | 지상 4층 | 2944600 | 600 | 0.16 | 0.006 | 0.3
2944959 | 지상 4층 | 지상 4층 | 2944600 | 1100 | 0.285 | 0.011 | 0.56
2944960 | 지상 4층 | 지상 4층 | 2944600 | 1100 | 0.285 | 0.011 | 0.56
2944961 | 지상 4층 | 지상 4층 | 2944600 | 1100 | 0.285 | 0.011 | 0.56
2944962 | 지상 4층 | 지상 4층 | 2944600 | 1100 | 0.285 | 0.011 | 0.56
2944963 | 지상 4층 | 지상 4층 | 2944600 | 1100 | 0.285 | 0.011 | 0.56
2944964 | 지상 4층 | 지상 4층 | 2944600 | 1100 | 0.285 | 0.011 | 0.56
2944965 | 지상 4층 | 지상 4층 | 2944600 | 1100 | 0.285 | 0.011 | 0.56
2944966 | 지상 4층 | 지상 4층 | 2944600 | 1100 | 0.285 | 0.011 | 0.56
2944967 | 지상 4층 | 지상 4층 | 2944600 | 1100 | 0.285 | 0.011 | 0.56
2944968 | 지상 4층 | 지상 4층 | 2944600 | 1100 | 0.285 | 0.011 | 0.56
2944969 | 지상 4층 | 지상 4층 | 2944600 | 1100 | 0.285 | 0.011 | 0.56
2944970 | 지상 4층 | 지상 4층 | 2944600 | 1100 | 0.285 | 0.011 | 0.56
2944971 | 지상 4층 | 지상 4층 | 2944600 | 1100 | 0.285 | 0.011 | 0.56
2945035 | 지상 4층 | 지상 4층 | 2944600 | 1010 | 0.2625 | 0.0101 | 0.525
2945036 | 지상 4층 | 지상 4층 | 2944600 | 970 | 0.2525 | 0.0097 | 0.505
2945037 | 지상 4층 | 지상 4층 | 2944600 | 915 | 0.23875 | 0.00915 | 0.4775
2945038 | 지상 4층 | 지상 4층 | 2944600 | 915 | 0.23875 | 0.00915 | 0.4775
2945039 | 지상 4층 | 지상 4층 | 2944600 | 915 | 0.23875 | 0.00915 | 0.4775
2945040 | 지상 4층 | 지상 4층 | 2944600 | 915 | 0.23875 | 0.00915 | 0.4775
2945041 | 지상 4층 | 지상 4층 | 2944600 | 915 | 0.23875 | 0.00915 | 0.4775
2945042 | 지상 4층 | 지상 4층 | 2944600 | 915 | 0.23875 | 0.00915 | 0.4775
2945043 | 지상 4층 | 지상 4층 | 2944600 | 915 | 0.23875 | 0.00915 | 0.4775
2945044 | 지상 4층 | 지상 4층 | 2944600 | 1015 | 0.26375 | 0.01015 | 0.5275
2945055 | 지상 4층 | 지상 4층 | 2944600 | 970 | 0.2525 | 0.0097 | 0.505
2945056 | 지상 4층 | 지상 4층 | 2944600 | 915 | 0.23875 | 0.00915 | 0.4775
2945057 | 지상 4층 | 지상 4층 | 2944600 | 915 | 0.23875 | 0.00915 | 0.4775
2945058 | 지상 4층 | 지상 4층 | 2944600 | 915 | 0.23875 | 0.00915 | 0.4775
2945059 | 지상 4층 | 지상 4층 | 2944600 | 915 | 0.23875 | 0.00915 | 0.4775
2945060 | 지상 4층 | 지상 4층 | 2944600 | 915 | 0.23875 | 0.00915 | 0.4775
2945061 | 지상 4층 | 지상 4층 | 2944600 | 915 | 0.23875 | 0.00915 | 0.4775
2945062 | 지상 4층 | 지상 4층 | 2944600 | 915 | 0.23875 | 0.00915 | 0.4775
2945063 | 지상 4층 | 지상 4층 | 2944600 | 1015 | 0.26375 | 0.01015 | 0.5275
2945064 | 지상 4층 | 지상 4층 | 2944600 | 892.808 | 0.233202 | 0.00892808 | 0.466404
2945065 | 지상 4층 | 지상 4층 | 2944600 | 970 | 0.2525 | 0.0097 | 0.505
2945066 | 지상 4층 | 지상 4층 | 2944600 | 915 | 0.23875 | 0.00915 | 0.4775
2945067 | 지상 4층 | 지상 4층 | 2944600 | 915 | 0.23875 | 0.00915 | 0.4775
2945068 | 지상 4층 | 지상 4층 | 2944600 | 915 | 0.23875 | 0.00915 | 0.4775
2945069 | 지상 4층 | 지상 4층 | 2944600 | 915 | 0.23875 | 0.00915 | 0.4775
2945070 | 지상 4층 | 지상 4층 | 2944600 | 915 | 0.23875 | 0.00915 | 0.4775
2945071 | 지상 4층 | 지상 4층 | 2944600 | 915 | 0.23875 | 0.00915 | 0.4775
2945072 | 지상 4층 | 지상 4층 | 2944600 | 915 | 0.23875 | 0.00915 | 0.4775
2945073 | 지상 4층 | 지상 4층 | 2944600 | 1015 | 0.26375 | 0.01015 | 0.5275
2945074 | 지상 4층 | 지상 4층 | 2944600 | 892.808 | 0.233202 | 0.00892808 | 0.466404
2945085 | 지상 4층 | 지상 4층 | 2944600 | 920 | 0.24 | 0.0092 | 0.47
2945086 | 지상 4층 | 지상 4층 | 2944600 | 920 | 0.24 | 0.0092 | 0.47
2945087 | 지상 4층 | 지상 4층 | 2944600 | 920 | 0.24 | 0.0092 | 0.47
2945088 | 지상 4층 | 지상 4층 | 2944600 | 920 | 0.24 | 0.0092 | 0.47
2945089 | 지상 4층 | 지상 4층 | 2944600 | 920 | 0.24 | 0.0092 | 0.47
2945090 | 지상 4층 | 지상 4층 | 2944600 | 920 | 0.24 | 0.0092 | 0.47
2945091 | 지상 4층 | 지상 4층 | 2944600 | 920 | 0.24 | 0.0092 | 0.47
2945092 | 지상 4층 | 지상 4층 | 2944600 | 920 | 0.24 | 0.0092 | 0.47
2945093 | 지상 4층 | 지상 4층 | 2944600 | 920 | 0.24 | 0.0092 | 0.47
2945094 | 지상 4층 | 지상 4층 | 2944600 | 920 | 0.24 | 0.0092 | 0.47
2945095 | 지상 4층 | 지상 4층 | 2944600 | 600 | 0.16 | 0.006 | 0.3
2945096 | 지상 4층 | 지상 4층 | 2944600 | 600 | 0.16 | 0.006 | 0.3
2945097 | 지상 4층 | 지상 4층 | 2944600 | 600 | 0.16 | 0.006 | 0.3
2945098 | 지상 4층 | 지상 4층 | 2944600 | 600 | 0.16 | 0.006 | 0.3
2945099 | 지상 4층 | 지상 4층 | 2944600 | 600 | 0.16 | 0.006 | 0.3
2945100 | 지상 4층 | 지상 4층 | 2944600 | 600 | 0.16 | 0.006 | 0.3
2945101 | 지상 4층 | 지상 4층 | 2944600 | 600 | 0.16 | 0.006 | 0.3
2945102 | 지상 4층 | 지상 4층 | 2944600 | 600 | 0.16 | 0.006 | 0.3
2945103 | 지상 4층 | 지상 4층 | 2944600 | 600 | 0.16 | 0.006 | 0.3
2945104 | 지상 4층 | 지상 4층 | 2944600 | 600 | 0.16 | 0.006 | 0.3
2945105 | 지상 4층 | 지상 4층 | 2944600 | 1100 | 0.285 | 0.011 | 0.56
2945106 | 지상 4층 | 지상 4층 | 2944600 | 1100 | 0.285 | 0.011 | 0.56
2945107 | 지상 4층 | 지상 4층 | 2944600 | 1100 | 0.285 | 0.011 | 0.56
2945108 | 지상 4층 | 지상 4층 | 2944600 | 1100 | 0.285 | 0.011 | 0.56
2945109 | 지상 4층 | 지상 4층 | 2944600 | 1100 | 0.285 | 0.011 | 0.56
2945110 | 지상 4층 | 지상 4층 | 2944600 | 1100 | 0.285 | 0.011 | 0.56
2945111 | 지상 4층 | 지상 4층 | 2944600 | 1100 | 0.285 | 0.011 | 0.56
2945112 | 지상 4층 | 지상 4층 | 2944600 | 1100 | 0.285 | 0.011 | 0.56
2945113 | 지상 4층 | 지상 4층 | 2944600 | 1100 | 0.285 | 0.011 | 0.56
2945114 | 지상 4층 | 지상 4층 | 2944600 | 1100 | 0.285 | 0.011 | 0.56
2945131 | 지상 4층 | 지상 4층 | 2944600 | 1010 | 0.2625 | 0.0101 | 0.525
2945132 | 지상 4층 | 지상 4층 | 2944600 | 1010 | 0.2625 | 0.0101 | 0.525
2945134 | 지상 4층 | 지상 4층 | 2944600 | 910 | 0.2375 | 0.0091 | 0.475
2945135 | 지상 4층 | 지상 4층 | 2944600 | 920 | 0.24 | 0.0092 | 0.47
2945136 | 지상 4층 | 지상 4층 | 2944600 | 600 | 0.16 | 0.006 | 0.3
2945137 | 지상 4층 | 지상 4층 | 2944600 | 1100 | 0.285 | 0.011 | 0.56
2945777 | 지상 3층 | 지상 3층 | 2945775 | 912.605 | 0.238151 | 0.00912605 | 0.476303
2945778 | 지상 3층 | 지상 3층 | 2945775 | 783.395 | 0.205849 | 0.00783395 | 0.411697
2945780 | 지상 3층 | 지상 3층 | 2945775 | 1070 | 0.2775 | 0.0107 | 0.545
2945784 | 지상 3층 | 지상 3층 | 2945775 | 600 | 0.16 | 0.006 | 0.3
2945789 | 지상 3층 | 지상 3층 | 2945775 | 950 | 0.2475 | 0.0095 | 0.485
2945876 | 지상 3층 | 지상 3층 | 2945775 | 783.395 | 0.205849 | 0.00783395 | 0.411697
2945877 | 지상 3층 | 지상 3층 | 2945775 | 700 | 0.185 | 0.007 | 0.37
2945878 | 지상 3층 | 지상 3층 | 2945775 | 700 | 0.185 | 0.007 | 0.37
2945879 | 지상 3층 | 지상 3층 | 2945775 | 700 | 0.185 | 0.007 | 0.37
2945880 | 지상 3층 | 지상 3층 | 2945775 | 950 | 0.2475 | 0.0095 | 0.485
2945881 | 지상 3층 | 지상 3층 | 2945775 | 600 | 0.16 | 0.006 | 0.3
2945882 | 지상 3층 | 지상 3층 | 2945775 | 1070 | 0.2775 | 0.0107 | 0.545
2945887 | 지상 3층 | 지상 3층 | 2945775 | 700 | 0.185 | 0.007 | 0.37
2945888 | 지상 3층 | 지상 3층 | 2945775 | 729 | 0.19225 | 0.00729 | 0.3845
2945889 | 지상 3층 | 지상 3층 | 2945775 | 729 | 0.19225 | 0.00729 | 0.3845
2945890 | 지상 3층 | 지상 3층 | 2945775 | 729 | 0.19225 | 0.00729 | 0.3845
2945891 | 지상 3층 | 지상 3층 | 2945775 | 950 | 0.2475 | 0.0095 | 0.485
2945892 | 지상 3층 | 지상 3층 | 2945775 | 600 | 0.16 | 0.006 | 0.3
2945893 | 지상 3층 | 지상 3층 | 2945775 | 1070 | 0.2775 | 0.0107 | 0.545
2945898 | 지상 3층 | 지상 3층 | 2945775 | 729 | 0.19225 | 0.00729 | 0.3845
2945899 | 지상 3층 | 지상 3층 | 2945775 | 729 | 0.19225 | 0.00729 | 0.3845
2945900 | 지상 3층 | 지상 3층 | 2945775 | 729 | 0.19225 | 0.00729 | 0.3845
2945901 | 지상 3층 | 지상 3층 | 2945775 | 729 | 0.19225 | 0.00729 | 0.3845
2945902 | 지상 3층 | 지상 3층 | 2945775 | 950 | 0.2475 | 0.0095 | 0.485
2945903 | 지상 3층 | 지상 3층 | 2945775 | 600 | 0.16 | 0.006 | 0.3
2945904 | 지상 3층 | 지상 3층 | 2945775 | 1070 | 0.2775 | 0.0107 | 0.545
2945909 | 지상 3층 | 지상 3층 | 2945775 | 729 | 0.19225 | 0.00729 | 0.3845
2945910 | 지상 3층 | 지상 3층 | 2945775 | 729 | 0.19225 | 0.00729 | 0.3845
2945911 | 지상 3층 | 지상 3층 | 2945775 | 729 | 0.19225 | 0.00729 | 0.3845
2945912 | 지상 3층 | 지상 3층 | 2945775 | 729 | 0.19225 | 0.00729 | 0.3845
2945913 | 지상 3층 | 지상 3층 | 2945775 | 950 | 0.2475 | 0.0095 | 0.485
2945914 | 지상 3층 | 지상 3층 | 2945775 | 600 | 0.16 | 0.006 | 0.3
2945915 | 지상 3층 | 지상 3층 | 2945775 | 1070 | 0.2775 | 0.0107 | 0.545
2945920 | 지상 3층 | 지상 3층 | 2945775 | 729 | 0.19225 | 0.00729 | 0.3845
2945921 | 지상 3층 | 지상 3층 | 2945775 | 729 | 0.19225 | 0.00729 | 0.3845
2945922 | 지상 3층 | 지상 3층 | 2945775 | 729 | 0.19225 | 0.00729 | 0.3845
2945923 | 지상 3층 | 지상 3층 | 2945775 | 729 | 0.19225 | 0.00729 | 0.3845
2945924 | 지상 3층 | 지상 3층 | 2945775 | 950 | 0.2475 | 0.0095 | 0.485
2945925 | 지상 3층 | 지상 3층 | 2945775 | 600 | 0.16 | 0.006 | 0.3
2945926 | 지상 3층 | 지상 3층 | 2945775 | 1070 | 0.2775 | 0.0107 | 0.545
2945931 | 지상 3층 | 지상 3층 | 2945775 | 729 | 0.19225 | 0.00729 | 0.3845
2945932 | 지상 3층 | 지상 3층 | 2945775 | 729 | 0.19225 | 0.00729 | 0.3845
2945933 | 지상 3층 | 지상 3층 | 2945775 | 729 | 0.19225 | 0.00729 | 0.3845
2945934 | 지상 3층 | 지상 3층 | 2945775 | 729 | 0.19225 | 0.00729 | 0.3845
2945935 | 지상 3층 | 지상 3층 | 2945775 | 950 | 0.2475 | 0.0095 | 0.485
2945936 | 지상 3층 | 지상 3층 | 2945775 | 600 | 0.16 | 0.006 | 0.3
2945937 | 지상 3층 | 지상 3층 | 2945775 | 1070 | 0.2775 | 0.0107 | 0.545
2945942 | 지상 3층 | 지상 3층 | 2945775 | 729 | 0.19225 | 0.00729 | 0.3845
2945943 | 지상 3층 | 지상 3층 | 2945775 | 729 | 0.19225 | 0.00729 | 0.3845
2945944 | 지상 3층 | 지상 3층 | 2945775 | 729 | 0.19225 | 0.00729 | 0.3845
2945945 | 지상 3층 | 지상 3층 | 2945775 | 729 | 0.19225 | 0.00729 | 0.3845
2945946 | 지상 3층 | 지상 3층 | 2945775 | 950 | 0.2475 | 0.0095 | 0.485
2945947 | 지상 3층 | 지상 3층 | 2945775 | 600 | 0.16 | 0.006 | 0.3
2945948 | 지상 3층 | 지상 3층 | 2945775 | 1070 | 0.2775 | 0.0107 | 0.545
2945953 | 지상 3층 | 지상 3층 | 2945775 | 729 | 0.19225 | 0.00729 | 0.3845
2945954 | 지상 3층 | 지상 3층 | 2945775 | 789 | 0.20725 | 0.00789 | 0.4145
2945955 | 지상 3층 | 지상 3층 | 2945775 | 789 | 0.20725 | 0.00789 | 0.4145
2945956 | 지상 3층 | 지상 3층 | 2945775 | 789 | 0.20725 | 0.00789 | 0.4145
2945957 | 지상 3층 | 지상 3층 | 2945775 | 950 | 0.2475 | 0.0095 | 0.485
2945958 | 지상 3층 | 지상 3층 | 2945775 | 600 | 0.16 | 0.006 | 0.3
2945959 | 지상 3층 | 지상 3층 | 2945775 | 1070 | 0.2775 | 0.0107 | 0.545
2945975 | 지상 3층 | 지상 3층 | 2945775 | 789 | 0.20725 | 0.00789 | 0.4145
2945976 | 지상 3층 | 지상 3층 | 2945775 | 1000 | 0.26 | 0.01 | 0.52
2945977 | 지상 3층 | 지상 3층 | 2945775 | 1000 | 0.26 | 0.01 | 0.52
2945978 | 지상 3층 | 지상 3층 | 2945775 | 1000 | 0.26 | 0.01 | 0.52
2945979 | 지상 3층 | 지상 3층 | 2945775 | 950 | 0.2475 | 0.0095 | 0.485
2945980 | 지상 3층 | 지상 3층 | 2945775 | 600 | 0.16 | 0.006 | 0.3
2945981 | 지상 3층 | 지상 3층 | 2945775 | 1070 | 0.2775 | 0.0107 | 0.545
2945986 | 지상 3층 | 지상 3층 | 2945775 | 716 | 0.189 | 0.00716 | 0.378
2945987 | 지상 3층 | 지상 3층 | 2945775 | 716 | 0.189 | 0.00716 | 0.378
2945988 | 지상 3층 | 지상 3층 | 2945775 | 716 | 0.189 | 0.00716 | 0.378
2945989 | 지상 3층 | 지상 3층 | 2945775 | 716 | 0.189 | 0.00716 | 0.378
2945990 | 지상 3층 | 지상 3층 | 2945775 | 950 | 0.2475 | 0.0095 | 0.485
2945991 | 지상 3층 | 지상 3층 | 2945775 | 600 | 0.16 | 0.006 | 0.3
2945992 | 지상 3층 | 지상 3층 | 2945775 | 1070 | 0.2775 | 0.0107 | 0.545
2945997 | 지상 3층 | 지상 3층 | 2945775 | 776 | 0.204 | 0.00776 | 0.408
2945998 | 지상 3층 | 지상 3층 | 2945775 | 776 | 0.204 | 0.00776 | 0.408
2945999 | 지상 3층 | 지상 3층 | 2945775 | 776 | 0.204 | 0.00776 | 0.408
2946000 | 지상 3층 | 지상 3층 | 2945775 | 1000 | 0.26 | 0.01 | 0.52
2946001 | 지상 3층 | 지상 3층 | 2945775 | 950 | 0.2475 | 0.0095 | 0.485
2946002 | 지상 3층 | 지상 3층 | 2945775 | 600 | 0.16 | 0.006 | 0.3
2946003 | 지상 3층 | 지상 3층 | 2945775 | 1070 | 0.2775 | 0.0107 | 0.545
2946008 | 지상 3층 | 지상 3층 | 2945775 | 716 | 0.189 | 0.00716 | 0.378
2946009 | 지상 3층 | 지상 3층 | 2945775 | 716 | 0.189 | 0.00716 | 0.378
2946010 | 지상 3층 | 지상 3층 | 2945775 | 716 | 0.189 | 0.00716 | 0.378
2946011 | 지상 3층 | 지상 3층 | 2945775 | 716 | 0.189 | 0.00716 | 0.378
2946012 | 지상 3층 | 지상 3층 | 2945775 | 950 | 0.2475 | 0.0095 | 0.485
2946013 | 지상 3층 | 지상 3층 | 2945775 | 600 | 0.16 | 0.006 | 0.3
2946014 | 지상 3층 | 지상 3층 | 2945775 | 1070 | 0.2775 | 0.0107 | 0.545
2946019 | 지상 3층 | 지상 3층 | 2945775 | 716 | 0.189 | 0.00716 | 0.378
2946020 | 지상 3층 | 지상 3층 | 2945775 | 716 | 0.189 | 0.00716 | 0.378
2946021 | 지상 3층 | 지상 3층 | 2945775 | 716 | 0.189 | 0.00716 | 0.378
2946022 | 지상 3층 | 지상 3층 | 2945775 | 716 | 0.189 | 0.00716 | 0.378
2946023 | 지상 3층 | 지상 3층 | 2945775 | 950 | 0.2475 | 0.0095 | 0.485
2946024 | 지상 3층 | 지상 3층 | 2945775 | 600 | 0.16 | 0.006 | 0.3
2946025 | 지상 3층 | 지상 3층 | 2945775 | 1070 | 0.2775 | 0.0107 | 0.545
2946026 | 지상 3층 | 지상 3층 | 2945775 | 716 | 0.189 | 0.00716 | 0.378
2946027 | 지상 3층 | 지상 3층 | 2945775 | 776 | 0.204 | 0.00776 | 0.408
2946028 | 지상 3층 | 지상 3층 | 2945775 | 776 | 0.204 | 0.00776 | 0.408
2946029 | 지상 3층 | 지상 3층 | 2945775 | 776 | 0.204 | 0.00776 | 0.408
2946038 | 지상 3층 | 지상 3층 | 2945775 | 950 | 0.2475 | 0.0095 | 0.485
2946039 | 지상 3층 | 지상 3층 | 2945775 | 600 | 0.16 | 0.006 | 0.3
2946040 | 지상 3층 | 지상 3층 | 2945775 | 1070 | 0.2775 | 0.0107 | 0.545
2946045 | 지상 3층 | 지상 3층 | 2945775 | 1000 | 0.26 | 0.01 | 0.52
2946046 | 지상 3층 | 지상 3층 | 2945775 | 776 | 0.204 | 0.00776 | 0.408
2946047 | 지상 3층 | 지상 3층 | 2945775 | 776 | 0.204 | 0.00776 | 0.408
2946048 | 지상 3층 | 지상 3층 | 2945775 | 776 | 0.204 | 0.00776 | 0.408
2946056 | 지상 3층 | 지상 3층 | 2945775 | 716 | 0.189 | 0.00716 | 0.378
2946057 | 지상 3층 | 지상 3층 | 2945775 | 716 | 0.189 | 0.00716 | 0.378
2946058 | 지상 3층 | 지상 3층 | 2945775 | 716 | 0.189 | 0.00716 | 0.378
2946059 | 지상 3층 | 지상 3층 | 2945775 | 716 | 0.189 | 0.00716 | 0.378
2946060 | 지상 3층 | 지상 3층 | 2945775 | 950 | 0.2475 | 0.0095 | 0.485
2946061 | 지상 3층 | 지상 3층 | 2945775 | 600 | 0.16 | 0.006 | 0.3
2946062 | 지상 3층 | 지상 3층 | 2945775 | 1070 | 0.2775 | 0.0107 | 0.545
2946067 | 지상 3층 | 지상 3층 | 2945775 | 716 | 0.189 | 0.00716 | 0.378
2946068 | 지상 3층 | 지상 3층 | 2945775 | 716 | 0.189 | 0.00716 | 0.378
2946069 | 지상 3층 | 지상 3층 | 2945775 | 716 | 0.189 | 0.00716 | 0.378
2946070 | 지상 3층 | 지상 3층 | 2945775 | 716 | 0.189 | 0.00716 | 0.378
2946071 | 지상 3층 | 지상 3층 | 2945775 | 950 | 0.2475 | 0.0095 | 0.485
2946072 | 지상 3층 | 지상 3층 | 2945775 | 600 | 0.16 | 0.006 | 0.3
2946073 | 지상 3층 | 지상 3층 | 2945775 | 1070 | 0.2775 | 0.0107 | 0.545
2946078 | 지상 3층 | 지상 3층 | 2945775 | 716 | 0.189 | 0.00716 | 0.378
2946079 | 지상 3층 | 지상 3층 | 2945775 | 716 | 0.189 | 0.00716 | 0.378
2946080 | 지상 3층 | 지상 3층 | 2945775 | 716 | 0.189 | 0.00716 | 0.378
2946081 | 지상 3층 | 지상 3층 | 2945775 | 716 | 0.189 | 0.00716 | 0.378
2946082 | 지상 3층 | 지상 3층 | 2945775 | 950 | 0.2475 | 0.0095 | 0.485
2946083 | 지상 3층 | 지상 3층 | 2945775 | 600 | 0.16 | 0.006 | 0.3
2946084 | 지상 3층 | 지상 3층 | 2945775 | 1070 | 0.2775 | 0.0107 | 0.545
2946089 | 지상 3층 | 지상 3층 | 2945775 | 716 | 0.189 | 0.00716 | 0.378
2946090 | 지상 3층 | 지상 3층 | 2945775 | 642 | 0.1705 | 0.00642 | 0.341
2946091 | 지상 3층 | 지상 3층 | 2945775 | 642 | 0.1705 | 0.00642 | 0.341
2946092 | 지상 3층 | 지상 3층 | 2945775 | 642 | 0.1705 | 0.00642 | 0.341
2946093 | 지상 3층 | 지상 3층 | 2945775 | 950 | 0.2475 | 0.0095 | 0.485
2946094 | 지상 3층 | 지상 3층 | 2945775 | 600 | 0.16 | 0.006 | 0.3
2946095 | 지상 3층 | 지상 3층 | 2945775 | 1070 | 0.2775 | 0.0107 | 0.545
2946100 | 지상 3층 | 지상 3층 | 2945775 | 642 | 0.1705 | 0.00642 | 0.341
2946101 | 지상 3층 | 지상 3층 | 2945775 | 702 | 0.1855 | 0.00702 | 0.371
2946102 | 지상 3층 | 지상 3층 | 2945775 | 702 | 0.1855 | 0.00702 | 0.371
2946103 | 지상 3층 | 지상 3층 | 2945775 | 702 | 0.1855 | 0.00702 | 0.371
2946104 | 지상 3층 | 지상 3층 | 2945775 | 950 | 0.2475 | 0.0095 | 0.485
2946105 | 지상 3층 | 지상 3층 | 2945775 | 600 | 0.16 | 0.006 | 0.3
2946106 | 지상 3층 | 지상 3층 | 2945775 | 1070 | 0.2775 | 0.0107 | 0.545
2946111 | 지상 3층 | 지상 3층 | 2945775 | 702 | 0.1855 | 0.00702 | 0.371
2946112 | 지상 3층 | 지상 3층 | 2945775 | 912.605 | 0.238151 | 0.00912605 | 0.476303
2946113 | 지상 3층 | 지상 3층 | 2945775 | 912.605 | 0.238151 | 0.00912605 | 0.476303
2946114 | 지상 3층 | 지상 3층 | 2945775 | 912.605 | 0.238151 | 0.00912605 | 0.476303
2946115 | 지상 3층 | 지상 3층 | 2945775 | 950 | 0.2475 | 0.0095 | 0.485
2946116 | 지상 3층 | 지상 3층 | 2945775 | 600 | 0.16 | 0.006 | 0.3
2946117 | 지상 3층 | 지상 3층 | 2945775 | 1070 | 0.2775 | 0.0107 | 0.545
2946151 | 지상 3층 | 지상 3층 | 2945775 | 716 | 0.189 | 0.00716 | 0.378
2946152 | 지상 3층 | 지상 3층 | 2945775 | 716 | 0.189 | 0.00716 | 0.378
2946153 | 지상 3층 | 지상 3층 | 2945775 | 716 | 0.189 | 0.00716 | 0.378
2946154 | 지상 3층 | 지상 3층 | 2945775 | 716 | 0.189 | 0.00716 | 0.378
2946155 | 지상 3층 | 지상 3층 | 2945775 | 950 | 0.2475 | 0.0095 | 0.485
2946156 | 지상 3층 | 지상 3층 | 2945775 | 600 | 0.16 | 0.006 | 0.3
2946157 | 지상 3층 | 지상 3층 | 2945775 | 1070 | 0.2775 | 0.0107 | 0.545
2946162 | 지상 3층 | 지상 3층 | 2945775 | 716 | 0.189 | 0.00716 | 0.378
2946163 | 지상 3층 | 지상 3층 | 2945775 | 716 | 0.189 | 0.00716 | 0.378
2946164 | 지상 3층 | 지상 3층 | 2945775 | 716 | 0.189 | 0.00716 | 0.378
2946165 | 지상 3층 | 지상 3층 | 2945775 | 716 | 0.189 | 0.00716 | 0.378
2946166 | 지상 3층 | 지상 3층 | 2945775 | 950 | 0.2475 | 0.0095 | 0.485
2946167 | 지상 3층 | 지상 3층 | 2945775 | 600 | 0.16 | 0.006 | 0.3
2946168 | 지상 3층 | 지상 3층 | 2945775 | 1070 | 0.2775 | 0.0107 | 0.545
2946173 | 지상 3층 | 지상 3층 | 2945775 | 716 | 0.189 | 0.00716 | 0.378
2946174 | 지상 3층 | 지상 3층 | 2945775 | 716 | 0.189 | 0.00716 | 0.378
2946175 | 지상 3층 | 지상 3층 | 2945775 | 716 | 0.189 | 0.00716 | 0.378
2946176 | 지상 3층 | 지상 3층 | 2945775 | 716 | 0.189 | 0.00716 | 0.378
2946177 | 지상 3층 | 지상 3층 | 2945775 | 950 | 0.2475 | 0.0095 | 0.485
2946178 | 지상 3층 | 지상 3층 | 2945775 | 600 | 0.16 | 0.006 | 0.3
2946179 | 지상 3층 | 지상 3층 | 2945775 | 1070 | 0.2775 | 0.0107 | 0.545
2946184 | 지상 3층 | 지상 3층 | 2945775 | 950 | 0.2475 | 0.0095 | 0.485
2946185 | 지상 3층 | 지상 3층 | 2945775 | 600 | 0.16 | 0.006 | 0.3
2946186 | 지상 3층 | 지상 3층 | 2945775 | 1070 | 0.2775 | 0.0107 | 0.545
2946191 | 지상 3층 | 지상 3층 | 2945775 | 716 | 0.189 | 0.00716 | 0.378
2946192 | 지상 3층 | 지상 3층 | 2945775 | 716 | 0.189 | 0.00716 | 0.378
2946193 | 지상 3층 | 지상 3층 | 2945775 | 716 | 0.189 | 0.00716 | 0.378
2946194 | 지상 3층 | 지상 3층 | 2945775 | 716 | 0.189 | 0.00716 | 0.378
2946195 | 지상 3층 | 지상 3층 | 2945775 | 950 | 0.2475 | 0.0095 | 0.485
2946196 | 지상 3층 | 지상 3층 | 2945775 | 600 | 0.16 | 0.006 | 0.3
2946197 | 지상 3층 | 지상 3층 | 2945775 | 1070 | 0.2775 | 0.0107 | 0.545
2946202 | 지상 3층 | 지상 3층 | 2945775 | 716 | 0.189 | 0.00716 | 0.378
2946203 | 지상 3층 | 지상 3층 | 2945775 | 716 | 0.189 | 0.00716 | 0.378
2946204 | 지상 3층 | 지상 3층 | 2945775 | 716 | 0.189 | 0.00716 | 0.378
2946205 | 지상 3층 | 지상 3층 | 2945775 | 716 | 0.189 | 0.00716 | 0.378
2946206 | 지상 3층 | 지상 3층 | 2945775 | 950 | 0.2475 | 0.0095 | 0.485
2946207 | 지상 3층 | 지상 3층 | 2945775 | 600 | 0.16 | 0.006 | 0.3
2946208 | 지상 3층 | 지상 3층 | 2945775 | 1070 | 0.2775 | 0.0107 | 0.545
2946213 | 지상 3층 | 지상 3층 | 2945775 | 716 | 0.189 | 0.00716 | 0.378
2946214 | 지상 3층 | 지상 3층 | 2945775 | 716 | 0.189 | 0.00716 | 0.378
2946215 | 지상 3층 | 지상 3층 | 2945775 | 716 | 0.189 | 0.00716 | 0.378
2946216 | 지상 3층 | 지상 3층 | 2945775 | 716 | 0.189 | 0.00716 | 0.378
2946217 | 지상 3층 | 지상 3층 | 2945775 | 950 | 0.2475 | 0.0095 | 0.485
2946218 | 지상 3층 | 지상 3층 | 2945775 | 600 | 0.16 | 0.006 | 0.3
2946219 | 지상 3층 | 지상 3층 | 2945775 | 1070 | 0.2775 | 0.0107 | 0.545
2946224 | 지상 3층 | 지상 3층 | 2945775 | 716 | 0.189 | 0.00716 | 0.378
2946225 | 지상 3층 | 지상 3층 | 2945775 | 716 | 0.189 | 0.00716 | 0.378
2946226 | 지상 3층 | 지상 3층 | 2945775 | 716 | 0.189 | 0.00716 | 0.378
2946227 | 지상 3층 | 지상 3층 | 2945775 | 716 | 0.189 | 0.00716 | 0.378
2946228 | 지상 3층 | 지상 3층 | 2945775 | 950 | 0.2475 | 0.0095 | 0.485
2946229 | 지상 3층 | 지상 3층 | 2945775 | 600 | 0.16 | 0.006 | 0.3
2946230 | 지상 3층 | 지상 3층 | 2945775 | 1070 | 0.2775 | 0.0107 | 0.545
2946235 | 지상 3층 | 지상 3층 | 2945775 | 716 | 0.189 | 0.00716 | 0.378
2946236 | 지상 3층 | 지상 3층 | 2945775 | 716 | 0.189 | 0.00716 | 0.378
2946237 | 지상 3층 | 지상 3층 | 2945775 | 716 | 0.189 | 0.00716 | 0.378
2946238 | 지상 3층 | 지상 3층 | 2945775 | 716 | 0.189 | 0.00716 | 0.378
2946239 | 지상 3층 | 지상 3층 | 2945775 | 950 | 0.2475 | 0.0095 | 0.485
2946240 | 지상 3층 | 지상 3층 | 2945775 | 600 | 0.16 | 0.006 | 0.3
2946241 | 지상 3층 | 지상 3층 | 2945775 | 1070 | 0.2775 | 0.0107 | 0.545
2946246 | 지상 3층 | 지상 3층 | 2945775 | 1000 | 0.26 | 0.01 | 0.52
2946247 | 지상 3층 | 지상 3층 | 2945775 | 1000 | 0.26 | 0.01 | 0.52
2946248 | 지상 3층 | 지상 3층 | 2945775 | 1000 | 0.26 | 0.01 | 0.52
2946249 | 지상 3층 | 지상 3층 | 2945775 | 776 | 0.204 | 0.00776 | 0.408
2946250 | 지상 3층 | 지상 3층 | 2945775 | 950 | 0.2475 | 0.0095 | 0.485
2946251 | 지상 3층 | 지상 3층 | 2945775 | 600 | 0.16 | 0.006 | 0.3
2946252 | 지상 3층 | 지상 3층 | 2945775 | 1070 | 0.2775 | 0.0107 | 0.545
2946417 | 지상 3층 | 지상 3층 | 2945775 | 783.395 | 0.205849 | 0.00783395 | 0.411697
2946418 | 지상 3층 | 지상 3층 | 2945775 | 783.395 | 0.205849 | 0.00783395 | 0.411697
2946664 | 지상 3층 | 지상 3층 | 2945775 | 716 | 0.189 | 0.00716 | 0.378
2946665 | 지상 3층 | 지상 3층 | 2945775 | 716 | 0.189 | 0.00716 | 0.378
2946666 | 지상 3층 | 지상 3층 | 2945775 | 716 | 0.189 | 0.00716 | 0.378
2946667 | 지상 3층 | 지상 3층 | 2945775 | 716 | 0.189 | 0.00716 | 0.378
2946668 | 지상 3층 | 지상 3층 | 2945775 | 950 | 0.2475 | 0.0095 | 0.485
2946669 | 지상 3층 | 지상 3층 | 2945775 | 600 | 0.16 | 0.006 | 0.3
2946670 | 지상 3층 | 지상 3층 | 2945775 | 1070 | 0.2775 | 0.0107 | 0.545
2946703 | 지상 3층 | 지상 3층 | 2945775 | 716 | 0.189 | 0.00716 | 0.378
2946704 | 지상 3층 | 지상 3층 | 2945775 | 716 | 0.189 | 0.00716 | 0.378
2946705 | 지상 3층 | 지상 3층 | 2945775 | 716 | 0.189 | 0.00716 | 0.378
2946706 | 지상 3층 | 지상 3층 | 2945775 | 776 | 0.204 | 0.00776 | 0.408
2946707 | 지상 3층 | 지상 3층 | 2945775 | 950 | 0.2475 | 0.0095 | 0.485
2946708 | 지상 3층 | 지상 3층 | 2945775 | 600 | 0.16 | 0.006 | 0.3
2946709 | 지상 3층 | 지상 3층 | 2945775 | 1070 | 0.2775 | 0.0107 | 0.545
2947261 | 지상 3층 | 지상 3층 | 2945775 | 776 | 0.204 | 0.00776 | 0.408
2947262 | 지상 3층 | 지상 3층 | 2945775 | 716 | 0.189 | 0.00716 | 0.378
2947263 | 지상 3층 | 지상 3층 | 2945775 | 716 | 0.189 | 0.00716 | 0.378
2947264 | 지상 3층 | 지상 3층 | 2945775 | 716 | 0.189 | 0.00716 | 0.378
2947265 | 지상 3층 | 지상 3층 | 2945775 | 950 | 0.2475 | 0.0095 | 0.485
2947266 | 지상 3층 | 지상 3층 | 2945775 | 600 | 0.16 | 0.006 | 0.3
2947267 | 지상 3층 | 지상 3층 | 2945775 | 1070 | 0.2775 | 0.0107 | 0.545
2947779 | 지상 3층 | 지상 3층 | 2945775 | 729 | 0.19225 | 0.00729 | 0.3845
2947780 | 지상 3층 | 지상 3층 | 2945775 | 729 | 0.19225 | 0.00729 | 0.3845
2947781 | 지상 3층 | 지상 3층 | 2945775 | 729 | 0.19225 | 0.00729 | 0.3845
2947782 | 지상 3층 | 지상 3층 | 2945775 | 729 | 0.19225 | 0.00729 | 0.3845
2947783 | 지상 3층 | 지상 3층 | 2945775 | 950 | 0.2475 | 0.0095 | 0.485
2947784 | 지상 3층 | 지상 3층 | 2945775 | 600 | 0.16 | 0.006 | 0.3
2947785 | 지상 3층 | 지상 3층 | 2945775 | 1070 | 0.2775 | 0.0107 | 0.545
2948718 | 지상 4층 | 지상 4층 | 2948716 | 907.605 | 0.236901 | 0.00907605 | 0.473803
2948721 | 지상 4층 | 지상 4층 | 2948716 | 1050 | 0.2725 | 0.0105 | 0.535
2948725 | 지상 4층 | 지상 4층 | 2948716 | 600 | 0.16 | 0.006 | 0.3
2948729 | 지상 4층 | 지상 4층 | 2948716 | 1000 | 0.26 | 0.01 | 0.5
2948905 | 지상 4층 | 지상 4층 | 2948716 | 716 | 0.189 | 0.00716 | 0.378
2948906 | 지상 4층 | 지상 4층 | 2948716 | 716 | 0.189 | 0.00716 | 0.378
2948914 | 지상 4층 | 지상 4층 | 2948716 | 716 | 0.189 | 0.00716 | 0.378
2948916 | 지상 4층 | 지상 4층 | 2948716 | 716 | 0.189 | 0.00716 | 0.378
2948917 | 지상 4층 | 지상 4층 | 2948716 | 716 | 0.189 | 0.00716 | 0.378
2948918 | 지상 4층 | 지상 4층 | 2948716 | 1450 | 0.3725 | 0.0145 | 0.735
2948919 | 지상 4층 | 지상 4층 | 2948716 | 600 | 0.16 | 0.006 | 0.3
2948920 | 지상 4층 | 지상 4층 | 2948716 | 1050 | 0.2725 | 0.0105 | 0.535
2948925 | 지상 4층 | 지상 4층 | 2948716 | 716 | 0.189 | 0.00716 | 0.378
2948927 | 지상 4층 | 지상 4층 | 2948716 | 642 | 0.1705 | 0.00642 | 0.341
2948928 | 지상 4층 | 지상 4층 | 2948716 | 642 | 0.1705 | 0.00642 | 0.341
2948929 | 지상 4층 | 지상 4층 | 2948716 | 1450 | 0.3725 | 0.0145 | 0.735
2948930 | 지상 4층 | 지상 4층 | 2948716 | 600 | 0.16 | 0.006 | 0.3
2948931 | 지상 4층 | 지상 4층 | 2948716 | 1050 | 0.2725 | 0.0105 | 0.535
2948936 | 지상 4층 | 지상 4층 | 2948716 | 642 | 0.1705 | 0.00642 | 0.341
2948938 | 지상 4층 | 지상 4층 | 2948716 | 702 | 0.1855 | 0.00702 | 0.371
2948939 | 지상 4층 | 지상 4층 | 2948716 | 702 | 0.1855 | 0.00702 | 0.371
2948940 | 지상 4층 | 지상 4층 | 2948716 | 1450 | 0.3725 | 0.0145 | 0.735
2948941 | 지상 4층 | 지상 4층 | 2948716 | 600 | 0.16 | 0.006 | 0.3
2948942 | 지상 4층 | 지상 4층 | 2948716 | 1050 | 0.2725 | 0.0105 | 0.535
2948947 | 지상 4층 | 지상 4층 | 2948716 | 702 | 0.1855 | 0.00702 | 0.371
2948949 | 지상 4층 | 지상 4층 | 2948716 | 907.605 | 0.236901 | 0.00907605 | 0.473803
2948950 | 지상 4층 | 지상 4층 | 2948716 | 907.605 | 0.236901 | 0.00907605 | 0.473803
2948951 | 지상 4층 | 지상 4층 | 2948716 | 1450 | 0.3725 | 0.0145 | 0.735
2948952 | 지상 4층 | 지상 4층 | 2948716 | 600 | 0.16 | 0.006 | 0.3
2948953 | 지상 4층 | 지상 4층 | 2948716 | 1050 | 0.2725 | 0.0105 | 0.535
2948959 | 지상 4층 | 지상 4층 | 2948716 | 716 | 0.189 | 0.00716 | 0.378
2948960 | 지상 4층 | 지상 4층 | 2948716 | 716 | 0.189 | 0.00716 | 0.378
2948961 | 지상 4층 | 지상 4층 | 2948716 | 716 | 0.189 | 0.00716 | 0.378
2948962 | 지상 4층 | 지상 4층 | 2948716 | 1450 | 0.3725 | 0.0145 | 0.735
2948963 | 지상 4층 | 지상 4층 | 2948716 | 600 | 0.16 | 0.006 | 0.3
2948964 | 지상 4층 | 지상 4층 | 2948716 | 1050 | 0.2725 | 0.0105 | 0.535
2948970 | 지상 4층 | 지상 4층 | 2948716 | 716 | 0.189 | 0.00716 | 0.378
2948971 | 지상 4층 | 지상 4층 | 2948716 | 716 | 0.189 | 0.00716 | 0.378
2948972 | 지상 4층 | 지상 4층 | 2948716 | 716 | 0.189 | 0.00716 | 0.378
2948973 | 지상 4층 | 지상 4층 | 2948716 | 1450 | 0.3725 | 0.0145 | 0.735
2948974 | 지상 4층 | 지상 4층 | 2948716 | 600 | 0.16 | 0.006 | 0.3
2948975 | 지상 4층 | 지상 4층 | 2948716 | 1050 | 0.2725 | 0.0105 | 0.535
2948981 | 지상 4층 | 지상 4층 | 2948716 | 716 | 0.189 | 0.00716 | 0.378
2948982 | 지상 4층 | 지상 4층 | 2948716 | 716 | 0.189 | 0.00716 | 0.378
2948983 | 지상 4층 | 지상 4층 | 2948716 | 716 | 0.189 | 0.00716 | 0.378
2948984 | 지상 4층 | 지상 4층 | 2948716 | 1450 | 0.3725 | 0.0145 | 0.735
2948985 | 지상 4층 | 지상 4층 | 2948716 | 600 | 0.16 | 0.006 | 0.3
2948986 | 지상 4층 | 지상 4층 | 2948716 | 1050 | 0.2725 | 0.0105 | 0.535
2948991 | 지상 4층 | 지상 4층 | 2948716 | 1450 | 0.3725 | 0.0145 | 0.735
2948992 | 지상 4층 | 지상 4층 | 2948716 | 600 | 0.16 | 0.006 | 0.3
2948993 | 지상 4층 | 지상 4층 | 2948716 | 1050 | 0.2725 | 0.0105 | 0.535
2948999 | 지상 4층 | 지상 4층 | 2948716 | 716 | 0.189 | 0.00716 | 0.378
2949000 | 지상 4층 | 지상 4층 | 2948716 | 716 | 0.189 | 0.00716 | 0.378
2949001 | 지상 4층 | 지상 4층 | 2948716 | 716 | 0.189 | 0.00716 | 0.378
2949002 | 지상 4층 | 지상 4층 | 2948716 | 1450 | 0.3725 | 0.0145 | 0.735
2949003 | 지상 4층 | 지상 4층 | 2948716 | 600 | 0.16 | 0.006 | 0.3
2949004 | 지상 4층 | 지상 4층 | 2948716 | 1050 | 0.2725 | 0.0105 | 0.535
2949010 | 지상 4층 | 지상 4층 | 2948716 | 716 | 0.189 | 0.00716 | 0.378
2949011 | 지상 4층 | 지상 4층 | 2948716 | 716 | 0.189 | 0.00716 | 0.378
2949012 | 지상 4층 | 지상 4층 | 2948716 | 716 | 0.189 | 0.00716 | 0.378
2949013 | 지상 4층 | 지상 4층 | 2948716 | 1450 | 0.3725 | 0.0145 | 0.735
2949014 | 지상 4층 | 지상 4층 | 2948716 | 600 | 0.16 | 0.006 | 0.3
2949015 | 지상 4층 | 지상 4층 | 2948716 | 1050 | 0.2725 | 0.0105 | 0.535
2949021 | 지상 4층 | 지상 4층 | 2948716 | 716 | 0.189 | 0.00716 | 0.378
2949022 | 지상 4층 | 지상 4층 | 2948716 | 716 | 0.189 | 0.00716 | 0.378
2949023 | 지상 4층 | 지상 4층 | 2948716 | 716 | 0.189 | 0.00716 | 0.378
2949024 | 지상 4층 | 지상 4층 | 2948716 | 1450 | 0.3725 | 0.0145 | 0.735
2949025 | 지상 4층 | 지상 4층 | 2948716 | 600 | 0.16 | 0.006 | 0.3
2949026 | 지상 4층 | 지상 4층 | 2948716 | 1050 | 0.2725 | 0.0105 | 0.535
2949772 | 지상 4층 | 지상 4층 | 2948716 | 1450 | 0.3725 | 0.0145 | 0.735
2949773 | 지상 4층 | 지상 4층 | 2948716 | 716 | 0.189 | 0.00716 | 0.378
2949774 | 지상 4층 | 지상 4층 | 2948716 | 716 | 0.189 | 0.00716 | 0.378
2949775 | 지상 4층 | 지상 4층 | 2948716 | 716 | 0.189 | 0.00716 | 0.378
2949776 | 지상 4층 | 지상 4층 | 2948716 | 716 | 0.189 | 0.00716 | 0.378
2949777 | 지상 4층 | 지상 4층 | 2948716 | 716 | 0.189 | 0.00716 | 0.378
2949778 | 지상 4층 | 지상 4층 | 2948716 | 716 | 0.189 | 0.00716 | 0.378
2949779 | 지상 4층 | 지상 4층 | 2948716 | 716 | 0.189 | 0.00716 | 0.378
2949780 | 지상 4층 | 지상 4층 | 2948716 | 716 | 0.189 | 0.00716 | 0.378
2949781 | 지상 4층 | 지상 4층 | 2948716 | 642 | 0.1705 | 0.00642 | 0.341
2949782 | 지상 4층 | 지상 4층 | 2948716 | 702 | 0.1855 | 0.00702 | 0.371
2949783 | 지상 4층 | 지상 4층 | 2948716 | 907.605 | 0.236901 | 0.00907605 | 0.473803
2949784 | 지상 4층 | 지상 4층 | 2948716 | 1000 | 0.26 | 0.01 | 0.5
2949785 | 지상 4층 | 지상 4층 | 2948716 | 1000 | 0.26 | 0.01 | 0.5
2949786 | 지상 4층 | 지상 4층 | 2948716 | 1000 | 0.26 | 0.01 | 0.5
2949787 | 지상 4층 | 지상 4층 | 2948716 | 1000 | 0.26 | 0.01 | 0.5
2949788 | 지상 4층 | 지상 4층 | 2948716 | 1000 | 0.26 | 0.01 | 0.5
2949789 | 지상 4층 | 지상 4층 | 2948716 | 1000 | 0.26 | 0.01 | 0.5
2949790 | 지상 4층 | 지상 4층 | 2948716 | 1000 | 0.26 | 0.01 | 0.5
2949791 | 지상 4층 | 지상 4층 | 2948716 | 1000 | 0.26 | 0.01 | 0.5
2949792 | 지상 4층 | 지상 4층 | 2948716 | 1000 | 0.26 | 0.01 | 0.5
2949793 | 지상 4층 | 지상 4층 | 2948716 | 1000 | 0.26 | 0.01 | 0.5
2949794 | 지상 4층 | 지상 4층 | 2948716 | 1000 | 0.26 | 0.01 | 0.5
3189644 | 지상 4층 | 지상 4층 | 2948716 | 716 | 0.189 | 0.00716 | 0.378
3189646 | 지상 4층 | 지상 4층 | 2948716 | 822.395 | 0.215599 | 0.00822395 | 0.431197
3189647 | 지상 4층 | 지상 4층 | 2948716 | 822.395 | 0.215599 | 0.00822395 | 0.431197
3189648 | 지상 4층 | 지상 4층 | 2948716 | 822.395 | 0.215599 | 0.00822395 | 0.431197
3189745 | 지상 4층 | 지상 4층 | 2948716 | 716 | 0.189 | 0.00716 | 0.378
3189747 | 지상 4층 | 지상 4층 | 2948716 | 716 | 0.189 | 0.00716 | 0.378
3189748 | 지상 4층 | 지상 4층 | 2948716 | 716 | 0.189 | 0.00716 | 0.378
3189749 | 지상 4층 | 지상 4층 | 2948716 | 716 | 0.189 | 0.00716 | 0.378
3189750 | 지상 4층 | 지상 4층 | 2948716 | 1450 | 0.3725 | 0.0145 | 0.735
3189751 | 지상 4층 | 지상 4층 | 2948716 | 1000 | 0.26 | 0.01 | 0.5
3189752 | 지상 4층 | 지상 4층 | 2948716 | 600 | 0.16 | 0.006 | 0.3
3189753 | 지상 4층 | 지상 4층 | 2948716 | 1050 | 0.2725 | 0.0105 | 0.535
3189807 | 지상 4층 | 지상 4층 | 2948716 | 716 | 0.189 | 0.00716 | 0.378
3189809 | 지상 4층 | 지상 4층 | 2948716 | 716 | 0.189 | 0.00716 | 0.378
3189810 | 지상 4층 | 지상 4층 | 2948716 | 716 | 0.189 | 0.00716 | 0.378
3189811 | 지상 4층 | 지상 4층 | 2948716 | 716 | 0.189 | 0.00716 | 0.378
3189812 | 지상 4층 | 지상 4층 | 2948716 | 1450 | 0.3725 | 0.0145 | 0.735
3189813 | 지상 4층 | 지상 4층 | 2948716 | 1000 | 0.26 | 0.01 | 0.5
3189814 | 지상 4층 | 지상 4층 | 2948716 | 600 | 0.16 | 0.006 | 0.3
3189815 | 지상 4층 | 지상 4층 | 2948716 | 1050 | 0.2725 | 0.0105 | 0.535
3189864 | 지상 4층 | 지상 4층 | 2948716 | 822.395 | 0.215599 | 0.00822395 | 0.431197
3189866 | 지상 4층 | 지상 4층 | 2948716 | 716 | 0.189 | 0.00716 | 0.378
3189867 | 지상 4층 | 지상 4층 | 2948716 | 716 | 0.189 | 0.00716 | 0.378
3189868 | 지상 4층 | 지상 4층 | 2948716 | 716 | 0.189 | 0.00716 | 0.378
3189869 | 지상 4층 | 지상 4층 | 2948716 | 1450 | 0.3725 | 0.0145 | 0.735
3189870 | 지상 4층 | 지상 4층 | 2948716 | 1000 | 0.26 | 0.01 | 0.5
3189871 | 지상 4층 | 지상 4층 | 2948716 | 600 | 0.16 | 0.006 | 0.3
3189872 | 지상 4층 | 지상 4층 | 2948716 | 1050 | 0.2725 | 0.0105 | 0.535
2949934 | 지상 4층 | 지상 4층 | 2949931 | 840.5 | 0.220125 | 0.008405 | 0.44025
2949935 | 지상 4층 | 지상 4층 | 2949931 | 400 | 0.11 | 0.004 | 0.21
2949936 | 지상 4층 | 지상 4층 | 2949931 | 1100 | 0.285 | 0.011 | 0.56
2949939 | 지상 4층 | 지상 4층 | 2949931 | 1100 | 0.285 | 0.011 | 0.56
2949940 | 지상 4층 | 지상 4층 | 2949931 | 600 | 0.16 | 0.006 | 0.3
2949943 | 지상 4층 | 지상 4층 | 2949931 | 600 | 0.16 | 0.006 | 0.3
2949944 | 지상 4층 | 지상 4층 | 2949931 | 400 | 0.11 | 0.004 | 0.21
2949949 | 지상 4층 | 지상 4층 | 2949931 | 840.5 | 0.220125 | 0.008405 | 0.44025
2949950 | 지상 4층 | 지상 4층 | 2949931 | 700 | 0.185 | 0.007 | 0.37
2949951 | 지상 4층 | 지상 4층 | 2949931 | 700 | 0.185 | 0.007 | 0.37
2949952 | 지상 4층 | 지상 4층 | 2949931 | 700 | 0.185 | 0.007 | 0.37
2949953 | 지상 4층 | 지상 4층 | 2949931 | 400 | 0.11 | 0.004 | 0.21
2949954 | 지상 4층 | 지상 4층 | 2949931 | 600 | 0.16 | 0.006 | 0.3
2949955 | 지상 4층 | 지상 4층 | 2949931 | 1100 | 0.285 | 0.011 | 0.56
2949960 | 지상 4층 | 지상 4층 | 2949931 | 700 | 0.185 | 0.007 | 0.37
2949961 | 지상 4층 | 지상 4층 | 2949931 | 729 | 0.19225 | 0.00729 | 0.3845
2949962 | 지상 4층 | 지상 4층 | 2949931 | 729 | 0.19225 | 0.00729 | 0.3845
2949963 | 지상 4층 | 지상 4층 | 2949931 | 729 | 0.19225 | 0.00729 | 0.3845
2949964 | 지상 4층 | 지상 4층 | 2949931 | 400 | 0.11 | 0.004 | 0.21
2949965 | 지상 4층 | 지상 4층 | 2949931 | 600 | 0.16 | 0.006 | 0.3
2949966 | 지상 4층 | 지상 4층 | 2949931 | 1100 | 0.285 | 0.011 | 0.56
2949971 | 지상 4층 | 지상 4층 | 2949931 | 729 | 0.19225 | 0.00729 | 0.3845
2949972 | 지상 4층 | 지상 4층 | 2949931 | 729 | 0.19225 | 0.00729 | 0.3845
2949973 | 지상 4층 | 지상 4층 | 2949931 | 729 | 0.19225 | 0.00729 | 0.3845
2949974 | 지상 4층 | 지상 4층 | 2949931 | 729 | 0.19225 | 0.00729 | 0.3845
2949975 | 지상 4층 | 지상 4층 | 2949931 | 400 | 0.11 | 0.004 | 0.21
2949976 | 지상 4층 | 지상 4층 | 2949931 | 600 | 0.16 | 0.006 | 0.3
2949977 | 지상 4층 | 지상 4층 | 2949931 | 1100 | 0.285 | 0.011 | 0.56
2949982 | 지상 4층 | 지상 4층 | 2949931 | 729 | 0.19225 | 0.00729 | 0.3845
2949983 | 지상 4층 | 지상 4층 | 2949931 | 729 | 0.19225 | 0.00729 | 0.3845
2949984 | 지상 4층 | 지상 4층 | 2949931 | 729 | 0.19225 | 0.00729 | 0.3845
2949985 | 지상 4층 | 지상 4층 | 2949931 | 729 | 0.19225 | 0.00729 | 0.3845
2949986 | 지상 4층 | 지상 4층 | 2949931 | 400 | 0.11 | 0.004 | 0.21
2949987 | 지상 4층 | 지상 4층 | 2949931 | 600 | 0.16 | 0.006 | 0.3
2949988 | 지상 4층 | 지상 4층 | 2949931 | 1100 | 0.285 | 0.011 | 0.56
2949993 | 지상 4층 | 지상 4층 | 2949931 | 729 | 0.19225 | 0.00729 | 0.3845
2949994 | 지상 4층 | 지상 4층 | 2949931 | 729 | 0.19225 | 0.00729 | 0.3845
2949995 | 지상 4층 | 지상 4층 | 2949931 | 729 | 0.19225 | 0.00729 | 0.3845
2949996 | 지상 4층 | 지상 4층 | 2949931 | 729 | 0.19225 | 0.00729 | 0.3845
2949997 | 지상 4층 | 지상 4층 | 2949931 | 400 | 0.11 | 0.004 | 0.21
2949998 | 지상 4층 | 지상 4층 | 2949931 | 600 | 0.16 | 0.006 | 0.3
2949999 | 지상 4층 | 지상 4층 | 2949931 | 1100 | 0.285 | 0.011 | 0.56
2950004 | 지상 4층 | 지상 4층 | 2949931 | 729 | 0.19225 | 0.00729 | 0.3845
2950005 | 지상 4층 | 지상 4층 | 2949931 | 729 | 0.19225 | 0.00729 | 0.3845
2950006 | 지상 4층 | 지상 4층 | 2949931 | 729 | 0.19225 | 0.00729 | 0.3845
2950007 | 지상 4층 | 지상 4층 | 2949931 | 729 | 0.19225 | 0.00729 | 0.3845
2950008 | 지상 4층 | 지상 4층 | 2949931 | 400 | 0.11 | 0.004 | 0.21
2950009 | 지상 4층 | 지상 4층 | 2949931 | 600 | 0.16 | 0.006 | 0.3
2950010 | 지상 4층 | 지상 4층 | 2949931 | 1100 | 0.285 | 0.011 | 0.56
2950015 | 지상 4층 | 지상 4층 | 2949931 | 729 | 0.19225 | 0.00729 | 0.3845
2950016 | 지상 4층 | 지상 4층 | 2949931 | 729 | 0.19225 | 0.00729 | 0.3845
2950017 | 지상 4층 | 지상 4층 | 2949931 | 729 | 0.19225 | 0.00729 | 0.3845
2950018 | 지상 4층 | 지상 4층 | 2949931 | 729 | 0.19225 | 0.00729 | 0.3845
2950019 | 지상 4층 | 지상 4층 | 2949931 | 400 | 0.11 | 0.004 | 0.21
2950020 | 지상 4층 | 지상 4층 | 2949931 | 600 | 0.16 | 0.006 | 0.3
2950021 | 지상 4층 | 지상 4층 | 2949931 | 1100 | 0.285 | 0.011 | 0.56
2950026 | 지상 4층 | 지상 4층 | 2949931 | 729 | 0.19225 | 0.00729 | 0.3845
2950027 | 지상 4층 | 지상 4층 | 2949931 | 789 | 0.20725 | 0.00789 | 0.4145
2950028 | 지상 4층 | 지상 4층 | 2949931 | 789 | 0.20725 | 0.00789 | 0.4145
2950029 | 지상 4층 | 지상 4층 | 2949931 | 789 | 0.20725 | 0.00789 | 0.4145
2950030 | 지상 4층 | 지상 4층 | 2949931 | 400 | 0.11 | 0.004 | 0.21
2950031 | 지상 4층 | 지상 4층 | 2949931 | 600 | 0.16 | 0.006 | 0.3
2950032 | 지상 4층 | 지상 4층 | 2949931 | 1100 | 0.285 | 0.011 | 0.56
2950037 | 지상 4층 | 지상 4층 | 2949931 | 789 | 0.20725 | 0.00789 | 0.4145
2950038 | 지상 4층 | 지상 4층 | 2949931 | 1000 | 0.26 | 0.01 | 0.52
2950039 | 지상 4층 | 지상 4층 | 2949931 | 1000 | 0.26 | 0.01 | 0.52
2950040 | 지상 4층 | 지상 4층 | 2949931 | 1000 | 0.26 | 0.01 | 0.52
2950041 | 지상 4층 | 지상 4층 | 2949931 | 400 | 0.11 | 0.004 | 0.21
2950042 | 지상 4층 | 지상 4층 | 2949931 | 600 | 0.16 | 0.006 | 0.3
2950043 | 지상 4층 | 지상 4층 | 2949931 | 1100 | 0.285 | 0.011 | 0.56
2950048 | 지상 4층 | 지상 4층 | 2949931 | 716 | 0.189 | 0.00716 | 0.378
2950049 | 지상 4층 | 지상 4층 | 2949931 | 716 | 0.189 | 0.00716 | 0.378
2950050 | 지상 4층 | 지상 4층 | 2949931 | 716 | 0.189 | 0.00716 | 0.378
2950051 | 지상 4층 | 지상 4층 | 2949931 | 716 | 0.189 | 0.00716 | 0.378
2950052 | 지상 4층 | 지상 4층 | 2949931 | 400 | 0.11 | 0.004 | 0.21
2950053 | 지상 4층 | 지상 4층 | 2949931 | 600 | 0.16 | 0.006 | 0.3
2950054 | 지상 4층 | 지상 4층 | 2949931 | 1100 | 0.285 | 0.011 | 0.56
2950059 | 지상 4층 | 지상 4층 | 2949931 | 776 | 0.204 | 0.00776 | 0.408
2950060 | 지상 4층 | 지상 4층 | 2949931 | 776 | 0.204 | 0.00776 | 0.408
2950061 | 지상 4층 | 지상 4층 | 2949931 | 776 | 0.204 | 0.00776 | 0.408
2950062 | 지상 4층 | 지상 4층 | 2949931 | 1000 | 0.26 | 0.01 | 0.52
2950063 | 지상 4층 | 지상 4층 | 2949931 | 400 | 0.11 | 0.004 | 0.21
2950064 | 지상 4층 | 지상 4층 | 2949931 | 600 | 0.16 | 0.006 | 0.3
2950065 | 지상 4층 | 지상 4층 | 2949931 | 1100 | 0.285 | 0.011 | 0.56
2950070 | 지상 4층 | 지상 4층 | 2949931 | 716 | 0.189 | 0.00716 | 0.378
2950071 | 지상 4층 | 지상 4층 | 2949931 | 716 | 0.189 | 0.00716 | 0.378
2950072 | 지상 4층 | 지상 4층 | 2949931 | 716 | 0.189 | 0.00716 | 0.378
2950073 | 지상 4층 | 지상 4층 | 2949931 | 716 | 0.189 | 0.00716 | 0.378
2950074 | 지상 4층 | 지상 4층 | 2949931 | 400 | 0.11 | 0.004 | 0.21
2950075 | 지상 4층 | 지상 4층 | 2949931 | 600 | 0.16 | 0.006 | 0.3
2950076 | 지상 4층 | 지상 4층 | 2949931 | 1100 | 0.285 | 0.011 | 0.56
2950081 | 지상 4층 | 지상 4층 | 2949931 | 716 | 0.189 | 0.00716 | 0.378
2950082 | 지상 4층 | 지상 4층 | 2949931 | 716 | 0.189 | 0.00716 | 0.378
2950083 | 지상 4층 | 지상 4층 | 2949931 | 716 | 0.189 | 0.00716 | 0.378
2950084 | 지상 4층 | 지상 4층 | 2949931 | 716 | 0.189 | 0.00716 | 0.378
2950085 | 지상 4층 | 지상 4층 | 2949931 | 400 | 0.11 | 0.004 | 0.21
2950086 | 지상 4층 | 지상 4층 | 2949931 | 600 | 0.16 | 0.006 | 0.3
2950087 | 지상 4층 | 지상 4층 | 2949931 | 1100 | 0.285 | 0.011 | 0.56
2950088 | 지상 4층 | 지상 4층 | 2949931 | 716 | 0.189 | 0.00716 | 0.378
2950089 | 지상 4층 | 지상 4층 | 2949931 | 877.5 | 0.229375 | 0.008775 | 0.45875
2950090 | 지상 4층 | 지상 4층 | 2949931 | 877.5 | 0.229375 | 0.008775 | 0.45875
2950091 | 지상 4층 | 지상 4층 | 2949931 | 877.5 | 0.229375 | 0.008775 | 0.45875
2950096 | 지상 4층 | 지상 4층 | 2949931 | 400 | 0.11 | 0.004 | 0.21
2950097 | 지상 4층 | 지상 4층 | 2949931 | 600 | 0.16 | 0.006 | 0.3
2950098 | 지상 4층 | 지상 4층 | 2949931 | 1100 | 0.285 | 0.011 | 0.56
2950246 | 지상 4층 | 지상 4층 | 2949931 | 716 | 0.189 | 0.00716 | 0.378
2950247 | 지상 4층 | 지상 4층 | 2949931 | 716 | 0.189 | 0.00716 | 0.378
2950248 | 지상 4층 | 지상 4층 | 2949931 | 716 | 0.189 | 0.00716 | 0.378
2950249 | 지상 4층 | 지상 4층 | 2949931 | 716 | 0.189 | 0.00716 | 0.378
2950250 | 지상 4층 | 지상 4층 | 2949931 | 400 | 0.11 | 0.004 | 0.21
2950251 | 지상 4층 | 지상 4층 | 2949931 | 600 | 0.16 | 0.006 | 0.3
2950252 | 지상 4층 | 지상 4층 | 2949931 | 1100 | 0.285 | 0.011 | 0.56
2950257 | 지상 4층 | 지상 4층 | 2949931 | 716 | 0.189 | 0.00716 | 0.378
2950258 | 지상 4층 | 지상 4층 | 2949931 | 716 | 0.189 | 0.00716 | 0.378
2950259 | 지상 4층 | 지상 4층 | 2949931 | 716 | 0.189 | 0.00716 | 0.378
2950260 | 지상 4층 | 지상 4층 | 2949931 | 716 | 0.189 | 0.00716 | 0.378
2950261 | 지상 4층 | 지상 4층 | 2949931 | 400 | 0.11 | 0.004 | 0.21
2950262 | 지상 4층 | 지상 4층 | 2949931 | 600 | 0.16 | 0.006 | 0.3
2950263 | 지상 4층 | 지상 4층 | 2949931 | 1100 | 0.285 | 0.011 | 0.56
2950275 | 지상 4층 | 지상 4층 | 2949931 | 840.5 | 0.220125 | 0.008405 | 0.44025
2950276 | 지상 4층 | 지상 4층 | 2949931 | 840.5 | 0.220125 | 0.008405 | 0.44025
2950303 | 지상 4층 | 지상 4층 | 2949931 | 776 | 0.204 | 0.00776 | 0.408
2950304 | 지상 4층 | 지상 4층 | 2949931 | 716 | 0.189 | 0.00716 | 0.378
2950305 | 지상 4층 | 지상 4층 | 2949931 | 716 | 0.189 | 0.00716 | 0.378
2950306 | 지상 4층 | 지상 4층 | 2949931 | 716 | 0.189 | 0.00716 | 0.378
2950307 | 지상 4층 | 지상 4층 | 2949931 | 400 | 0.11 | 0.004 | 0.21
2950308 | 지상 4층 | 지상 4층 | 2949931 | 600 | 0.16 | 0.006 | 0.3
2950309 | 지상 4층 | 지상 4층 | 2949931 | 1100 | 0.285 | 0.011 | 0.56
2950314 | 지상 4층 | 지상 4층 | 2949931 | 729 | 0.19225 | 0.00729 | 0.3845
2950315 | 지상 4층 | 지상 4층 | 2949931 | 729 | 0.19225 | 0.00729 | 0.3845
2950316 | 지상 4층 | 지상 4층 | 2949931 | 729 | 0.19225 | 0.00729 | 0.3845
2950317 | 지상 4층 | 지상 4층 | 2949931 | 729 | 0.19225 | 0.00729 | 0.3845
2950318 | 지상 4층 | 지상 4층 | 2949931 | 400 | 0.11 | 0.004 | 0.21
2950319 | 지상 4층 | 지상 4층 | 2949931 | 600 | 0.16 | 0.006 | 0.3
2950320 | 지상 4층 | 지상 4층 | 2949931 | 1100 | 0.285 | 0.011 | 0.56
5897628 | 지상 4층 | 지상 4층 | 2949931 | 877.5 | 0.229375 | 0.008775 | 0.45875
2951078 | 지상 3층 | 지상 3층 | 2951075 | 904.999 | 0.23625 | 0.00904999 | 0.4725
2951079 | 지상 3층 | 지상 3층 | 2951075 | 1076.02 | 0.279004 | 0.0107602 | 0.558008
2951080 | 지상 3층 | 지상 3층 | 2951075 | 950 | 0.2475 | 0.0095 | 0.485
2951081 | 지상 3층 | 지상 3층 | 2951075 | 1070 | 0.2775 | 0.0107 | 0.545
2951924 | 지상 3층 | 지상 3층 | 2951075 | 600 | 0.16 | 0.006 | 0.3
2951925 | 지상 3층 | 지상 3층 | 2951075 | 950 | 0.2475 | 0.0095 | 0.485
2951926 | 지상 3층 | 지상 3층 | 2951075 | 1076.02 | 0.279004 | 0.0107602 | 0.558008
2952175 | 지상 3층 | 지상 3층 | 2951075 | 1070 | 0.2775 | 0.0107 | 0.545
2952176 | 지상 3층 | 지상 3층 | 2951075 | 600 | 0.16 | 0.006 | 0.3
2952177 | 지상 3층 | 지상 3층 | 2951075 | 1076.02 | 0.279004 | 0.0107602 | 0.558008
2952533 | 지상 3층 | 지상 3층 | 2951075 | 1076.02 | 0.279004 | 0.0107602 | 0.558008
2952534 | 지상 3층 | 지상 3층 | 2951075 | 929.999 | 0.2425 | 0.00929999 | 0.485
2952535 | 지상 3층 | 지상 3층 | 2951075 | 929.999 | 0.2425 | 0.00929999 | 0.485
2952536 | 지상 3층 | 지상 3층 | 2951075 | 929.999 | 0.2425 | 0.00929999 | 0.485
2952537 | 지상 3층 | 지상 3층 | 2951075 | 950 | 0.2475 | 0.0095 | 0.485
2952538 | 지상 3층 | 지상 3층 | 2951075 | 600 | 0.16 | 0.006 | 0.3
2952539 | 지상 3층 | 지상 3층 | 2951075 | 1070 | 0.2775 | 0.0107 | 0.545
2952711 | 지상 3층 | 지상 3층 | 2951075 | 929.999 | 0.2425 | 0.00929999 | 0.485
2952712 | 지상 3층 | 지상 3층 | 2951075 | 929.999 | 0.2425 | 0.00929999 | 0.485
2952713 | 지상 3층 | 지상 3층 | 2951075 | 929.999 | 0.2425 | 0.00929999 | 0.485
2952714 | 지상 3층 | 지상 3층 | 2951075 | 929.999 | 0.2425 | 0.00929999 | 0.485
2952715 | 지상 3층 | 지상 3층 | 2951075 | 950 | 0.2475 | 0.0095 | 0.485
2952716 | 지상 3층 | 지상 3층 | 2951075 | 600 | 0.16 | 0.006 | 0.3
2952717 | 지상 3층 | 지상 3층 | 2951075 | 1070 | 0.2775 | 0.0107 | 0.545
2952801 | 지상 3층 | 지상 3층 | 2951075 | 929.999 | 0.2425 | 0.00929999 | 0.485
2952802 | 지상 3층 | 지상 3층 | 2951075 | 929.999 | 0.2425 | 0.00929999 | 0.485
2952803 | 지상 3층 | 지상 3층 | 2951075 | 929.999 | 0.2425 | 0.00929999 | 0.485
2952804 | 지상 3층 | 지상 3층 | 2951075 | 929.999 | 0.2425 | 0.00929999 | 0.485
2952805 | 지상 3층 | 지상 3층 | 2951075 | 950 | 0.2475 | 0.0095 | 0.485
2952806 | 지상 3층 | 지상 3층 | 2951075 | 600 | 0.16 | 0.006 | 0.3
2952807 | 지상 3층 | 지상 3층 | 2951075 | 1070 | 0.2775 | 0.0107 | 0.545
2952839 | 지상 3층 | 지상 3층 | 2951075 | 929.999 | 0.2425 | 0.00929999 | 0.485
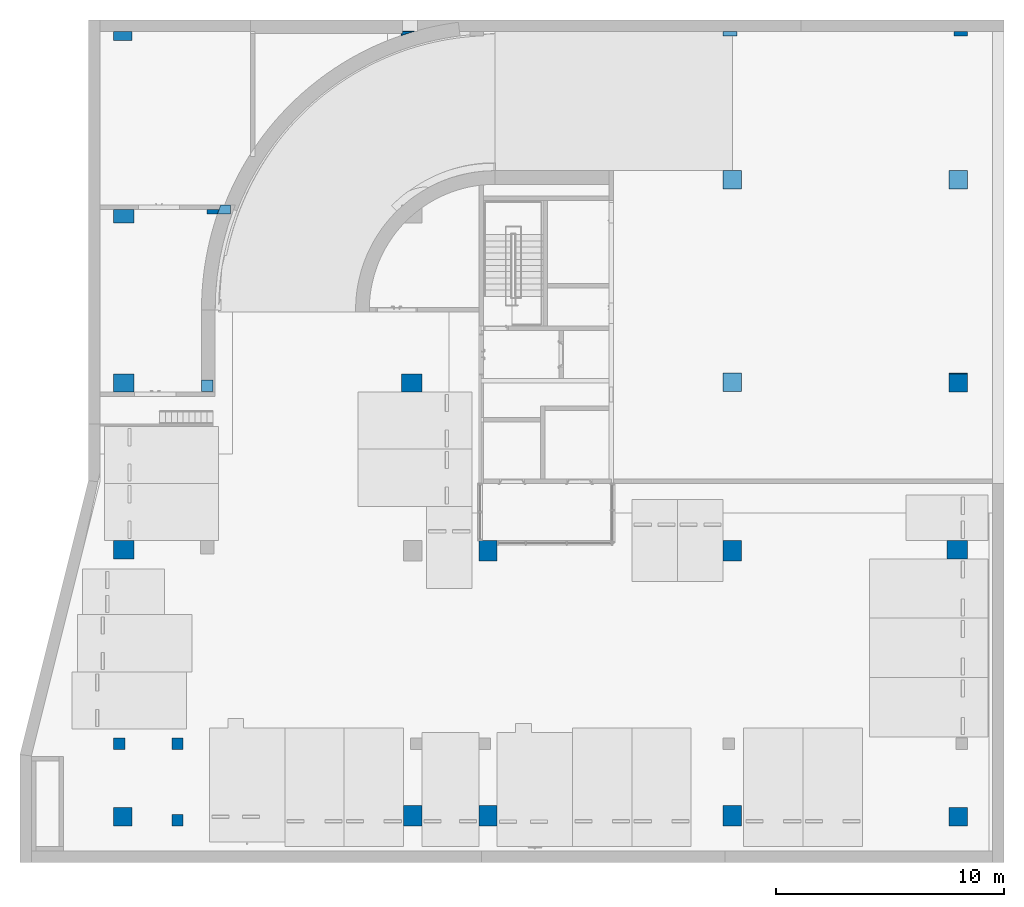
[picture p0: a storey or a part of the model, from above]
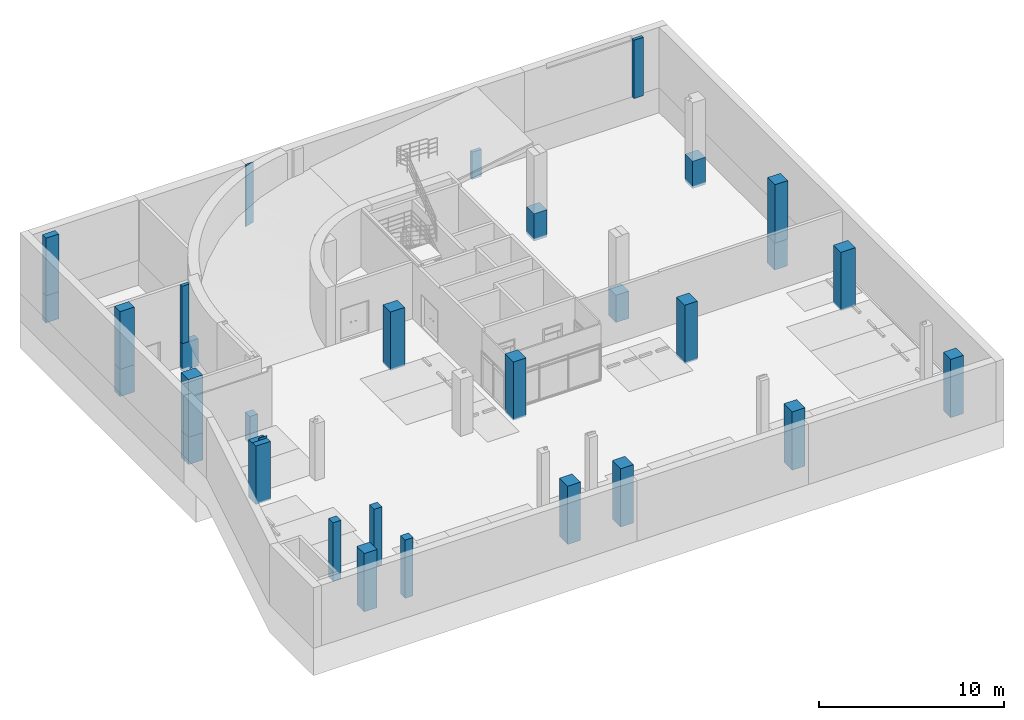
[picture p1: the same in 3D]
Properties of the parts of a building model (IFC2X3), part 18 of 39

# IfcMember: 직사각형 멀리언:CW200-직사각형 멀리언 50x200mm (8700)
Name (직사각형 멀리언:CW200-직사각형 멀리언 50x200mm:...) | In | 레벨 | 호스트 ID | 길이 (mm) = Span (mm) | 면적 (m2) = CrossSectionArea (m2) | 체적 (m3) = NetVolume (m3) | NetSurfaceArea (m2)
2952840 | 지상 3층 | 지상 3층 | 2951075 | 929.999 | 0.2425 | 0.00929999 | 0.485
2952841 | 지상 3층 | 지상 3층 | 2951075 | 929.999 | 0.2425 | 0.00929999 | 0.485
2952842 | 지상 3층 | 지상 3층 | 2951075 | 929.999 | 0.2425 | 0.00929999 | 0.485
2952843 | 지상 3층 | 지상 3층 | 2951075 | 950 | 0.2475 | 0.0095 | 0.485
2952844 | 지상 3층 | 지상 3층 | 2951075 | 600 | 0.16 | 0.006 | 0.3
2952845 | 지상 3층 | 지상 3층 | 2951075 | 1070 | 0.2775 | 0.0107 | 0.545
2952877 | 지상 3층 | 지상 3층 | 2951075 | 929.999 | 0.2425 | 0.00929999 | 0.485
2952878 | 지상 3층 | 지상 3층 | 2951075 | 929.999 | 0.2425 | 0.00929999 | 0.485
2952879 | 지상 3층 | 지상 3층 | 2951075 | 929.999 | 0.2425 | 0.00929999 | 0.485
2952880 | 지상 3층 | 지상 3층 | 2951075 | 929.999 | 0.2425 | 0.00929999 | 0.485
2952881 | 지상 3층 | 지상 3층 | 2951075 | 950 | 0.2475 | 0.0095 | 0.485
2952882 | 지상 3층 | 지상 3층 | 2951075 | 600 | 0.16 | 0.006 | 0.3
2952883 | 지상 3층 | 지상 3층 | 2951075 | 1070 | 0.2775 | 0.0107 | 0.545
2952915 | 지상 3층 | 지상 3층 | 2951075 | 929.999 | 0.2425 | 0.00929999 | 0.485
2952916 | 지상 3층 | 지상 3층 | 2951075 | 929.999 | 0.2425 | 0.00929999 | 0.485
2952917 | 지상 3층 | 지상 3층 | 2951075 | 929.999 | 0.2425 | 0.00929999 | 0.485
2952918 | 지상 3층 | 지상 3층 | 2951075 | 929.999 | 0.2425 | 0.00929999 | 0.485
2952919 | 지상 3층 | 지상 3층 | 2951075 | 950 | 0.2475 | 0.0095 | 0.485
2952920 | 지상 3층 | 지상 3층 | 2951075 | 600 | 0.16 | 0.006 | 0.3
2952921 | 지상 3층 | 지상 3층 | 2951075 | 1070 | 0.2775 | 0.0107 | 0.545
2952953 | 지상 3층 | 지상 3층 | 2951075 | 929.999 | 0.2425 | 0.00929999 | 0.485
2952954 | 지상 3층 | 지상 3층 | 2951075 | 929.999 | 0.2425 | 0.00929999 | 0.485
2952955 | 지상 3층 | 지상 3층 | 2951075 | 929.999 | 0.2425 | 0.00929999 | 0.485
2952956 | 지상 3층 | 지상 3층 | 2951075 | 929.999 | 0.2425 | 0.00929999 | 0.485
2952957 | 지상 3층 | 지상 3층 | 2951075 | 950 | 0.2475 | 0.0095 | 0.485
2952958 | 지상 3층 | 지상 3층 | 2951075 | 600 | 0.16 | 0.006 | 0.3
2952959 | 지상 3층 | 지상 3층 | 2951075 | 1070 | 0.2775 | 0.0107 | 0.545
2953130 | 지상 3층 | 지상 3층 | 2951075 | 929.999 | 0.2425 | 0.00929999 | 0.485
2953131 | 지상 3층 | 지상 3층 | 2951075 | 904.999 | 0.23625 | 0.00904999 | 0.4725
2953132 | 지상 3층 | 지상 3층 | 2951075 | 904.999 | 0.23625 | 0.00904999 | 0.4725
2953133 | 지상 3층 | 지상 3층 | 2951075 | 904.999 | 0.23625 | 0.00904999 | 0.4725
2953134 | 지상 3층 | 지상 3층 | 2951075 | 950 | 0.2475 | 0.0095 | 0.485
2953135 | 지상 3층 | 지상 3층 | 2951075 | 600 | 0.16 | 0.006 | 0.3
2953136 | 지상 3층 | 지상 3층 | 2951075 | 1070 | 0.2775 | 0.0107 | 0.545
2960448 | 지상 10층 | 지상 10층 | 2960446 | 912.5 | 0.238125 | 0.009125 | 0.47625
2960449 | 지상 10층 | 지상 10층 | 2960446 | 178.395 | 0.0545986 | 0.00178395 | 0.109197
2960451 | 지상 10층 | 지상 10층 | 2960446 | 2100 | 0.535 | 0.021 | 1.06
2960455 | 지상 10층 | 지상 10층 | 2960446 | 300 | 0.085 | 0.003 | 0.16
2960456 | 지상 10층 | 지상 10층 | 2960446 | 178.395 | 0.0545986 | 0.00178395 | 0.109197
2960460 | 지상 10층 | 지상 10층 | 2960446 | 600 | 0.16 | 0.006 | 0.3
2960461 | 지상 10층 | 지상 10층 | 2960446 | 178.395 | 0.0545986 | 0.00178395 | 0.109197
2960466 | 지상 10층 | 지상 10층 | 2960446 | 178.395 | 0.0545986 | 0.00178395 | 0.109197
2960467 | 지상 10층 | 지상 10층 | 2960446 | 828.5 | 0.217125 | 0.008285 | 0.42425
2960468 | 지상 10층 | 지상 10층 | 2960446 | 803.5 | 0.210875 | 0.008035 | 0.42175
2960469 | 지상 10층 | 지상 10층 | 2960446 | 803.5 | 0.210875 | 0.008035 | 0.42175
2960470 | 지상 10층 | 지상 10층 | 2960446 | 300 | 0.085 | 0.003 | 0.16
2960471 | 지상 10층 | 지상 10층 | 2960446 | 600 | 0.16 | 0.006 | 0.3
2960472 | 지상 10층 | 지상 10층 | 2960446 | 2100 | 0.535 | 0.021 | 1.06
2960477 | 지상 10층 | 지상 10층 | 2960446 | 828.5 | 0.217125 | 0.008285 | 0.42425
2960478 | 지상 10층 | 지상 10층 | 2960446 | 828.5 | 0.217125 | 0.008285 | 0.42425
2960479 | 지상 10층 | 지상 10층 | 2960446 | 803.5 | 0.210875 | 0.008035 | 0.42175
2960480 | 지상 10층 | 지상 10층 | 2960446 | 803.5 | 0.210875 | 0.008035 | 0.42175
2960481 | 지상 10층 | 지상 10층 | 2960446 | 300 | 0.085 | 0.003 | 0.16
2960482 | 지상 10층 | 지상 10층 | 2960446 | 600 | 0.16 | 0.006 | 0.3
2960483 | 지상 10층 | 지상 10층 | 2960446 | 2100 | 0.535 | 0.021 | 1.06
2960488 | 지상 10층 | 지상 10층 | 2960446 | 828.5 | 0.217125 | 0.008285 | 0.42425
2960489 | 지상 10층 | 지상 10층 | 2960446 | 828.5 | 0.217125 | 0.008285 | 0.42425
2960490 | 지상 10층 | 지상 10층 | 2960446 | 803.5 | 0.210875 | 0.008035 | 0.42175
2960491 | 지상 10층 | 지상 10층 | 2960446 | 803.5 | 0.210875 | 0.008035 | 0.42175
2960492 | 지상 10층 | 지상 10층 | 2960446 | 300 | 0.085 | 0.003 | 0.16
2960493 | 지상 10층 | 지상 10층 | 2960446 | 600 | 0.16 | 0.006 | 0.3
2960494 | 지상 10층 | 지상 10층 | 2960446 | 2100 | 0.535 | 0.021 | 1.06
2960499 | 지상 10층 | 지상 10층 | 2960446 | 828.5 | 0.217125 | 0.008285 | 0.42425
2960500 | 지상 10층 | 지상 10층 | 2960446 | 828.5 | 0.217125 | 0.008285 | 0.42425
2960501 | 지상 10층 | 지상 10층 | 2960446 | 803.5 | 0.210875 | 0.008035 | 0.42175
2960502 | 지상 10층 | 지상 10층 | 2960446 | 803.5 | 0.210875 | 0.008035 | 0.42175
2960503 | 지상 10층 | 지상 10층 | 2960446 | 300 | 0.085 | 0.003 | 0.16
2960504 | 지상 10층 | 지상 10층 | 2960446 | 600 | 0.16 | 0.006 | 0.3
2960505 | 지상 10층 | 지상 10층 | 2960446 | 2100 | 0.535 | 0.021 | 1.06
2960510 | 지상 10층 | 지상 10층 | 2960446 | 828.5 | 0.217125 | 0.008285 | 0.42425
2960511 | 지상 10층 | 지상 10층 | 2960446 | 1120 | 0.29 | 0.0112 | 0.58
2960512 | 지상 10층 | 지상 10층 | 2960446 | 1120 | 0.29 | 0.0112 | 0.58
2960513 | 지상 10층 | 지상 10층 | 2960446 | 1120 | 0.29 | 0.0112 | 0.58
2960514 | 지상 10층 | 지상 10층 | 2960446 | 300 | 0.085 | 0.003 | 0.16
2960515 | 지상 10층 | 지상 10층 | 2960446 | 600 | 0.16 | 0.006 | 0.3
2960516 | 지상 10층 | 지상 10층 | 2960446 | 2100 | 0.535 | 0.021 | 1.06
2960521 | 지상 10층 | 지상 10층 | 2960446 | 1120 | 0.29 | 0.0112 | 0.58
2960522 | 지상 10층 | 지상 10층 | 2960446 | 754 | 0.1985 | 0.00754 | 0.387
2960523 | 지상 10층 | 지상 10층 | 2960446 | 729 | 0.19225 | 0.00729 | 0.3845
2960524 | 지상 10층 | 지상 10층 | 2960446 | 729 | 0.19225 | 0.00729 | 0.3845
2960525 | 지상 10층 | 지상 10층 | 2960446 | 300 | 0.085 | 0.003 | 0.16
2960526 | 지상 10층 | 지상 10층 | 2960446 | 600 | 0.16 | 0.006 | 0.3
2960527 | 지상 10층 | 지상 10층 | 2960446 | 2100 | 0.535 | 0.021 | 1.06
2960532 | 지상 10층 | 지상 10층 | 2960446 | 754 | 0.1985 | 0.00754 | 0.387
2960533 | 지상 10층 | 지상 10층 | 2960446 | 754 | 0.1985 | 0.00754 | 0.387
2960534 | 지상 10층 | 지상 10층 | 2960446 | 729 | 0.19225 | 0.00729 | 0.3845
2960535 | 지상 10층 | 지상 10층 | 2960446 | 729 | 0.19225 | 0.00729 | 0.3845
2960536 | 지상 10층 | 지상 10층 | 2960446 | 300 | 0.085 | 0.003 | 0.16
2960537 | 지상 10층 | 지상 10층 | 2960446 | 600 | 0.16 | 0.006 | 0.3
2960538 | 지상 10층 | 지상 10층 | 2960446 | 2100 | 0.535 | 0.021 | 1.06
2960543 | 지상 10층 | 지상 10층 | 2960446 | 754 | 0.1985 | 0.00754 | 0.387
2960544 | 지상 10층 | 지상 10층 | 2960446 | 754 | 0.1985 | 0.00754 | 0.387
2960545 | 지상 10층 | 지상 10층 | 2960446 | 729 | 0.19225 | 0.00729 | 0.3845
2960546 | 지상 10층 | 지상 10층 | 2960446 | 729 | 0.19225 | 0.00729 | 0.3845
2960547 | 지상 10층 | 지상 10층 | 2960446 | 300 | 0.085 | 0.003 | 0.16
2960548 | 지상 10층 | 지상 10층 | 2960446 | 600 | 0.16 | 0.006 | 0.3
2960549 | 지상 10층 | 지상 10층 | 2960446 | 2100 | 0.535 | 0.021 | 1.06
2960554 | 지상 10층 | 지상 10층 | 2960446 | 754 | 0.1985 | 0.00754 | 0.387
2960555 | 지상 10층 | 지상 10층 | 2960446 | 754 | 0.1985 | 0.00754 | 0.387
2960556 | 지상 10층 | 지상 10층 | 2960446 | 729 | 0.19225 | 0.00729 | 0.3845
2960557 | 지상 10층 | 지상 10층 | 2960446 | 729 | 0.19225 | 0.00729 | 0.3845
2960558 | 지상 10층 | 지상 10층 | 2960446 | 300 | 0.085 | 0.003 | 0.16
2960559 | 지상 10층 | 지상 10층 | 2960446 | 600 | 0.16 | 0.006 | 0.3
2960560 | 지상 10층 | 지상 10층 | 2960446 | 2100 | 0.535 | 0.021 | 1.06
2960565 | 지상 10층 | 지상 10층 | 2960446 | 754 | 0.1985 | 0.00754 | 0.387
2960566 | 지상 10층 | 지상 10층 | 2960446 | 1120 | 0.29 | 0.0112 | 0.58
2960567 | 지상 10층 | 지상 10층 | 2960446 | 1120 | 0.29 | 0.0112 | 0.58
2960568 | 지상 10층 | 지상 10층 | 2960446 | 1120 | 0.29 | 0.0112 | 0.58
2960569 | 지상 10층 | 지상 10층 | 2960446 | 300 | 0.085 | 0.003 | 0.16
2960570 | 지상 10층 | 지상 10층 | 2960446 | 600 | 0.16 | 0.006 | 0.3
2960571 | 지상 10층 | 지상 10층 | 2960446 | 2100 | 0.535 | 0.021 | 1.06
2960576 | 지상 10층 | 지상 10층 | 2960446 | 1120 | 0.29 | 0.0112 | 0.58
2960577 | 지상 10층 | 지상 10층 | 2960446 | 741.5 | 0.195375 | 0.007415 | 0.38075
2960578 | 지상 10층 | 지상 10층 | 2960446 | 716.5 | 0.189125 | 0.007165 | 0.37825
2960579 | 지상 10층 | 지상 10층 | 2960446 | 716.5 | 0.189125 | 0.007165 | 0.37825
2960580 | 지상 10층 | 지상 10층 | 2960446 | 300 | 0.085 | 0.003 | 0.16
2960581 | 지상 10층 | 지상 10층 | 2960446 | 600 | 0.16 | 0.006 | 0.3
2960582 | 지상 10층 | 지상 10층 | 2960446 | 2100 | 0.535 | 0.021 | 1.06
2960587 | 지상 10층 | 지상 10층 | 2960446 | 741.5 | 0.195375 | 0.007415 | 0.38075
2960588 | 지상 10층 | 지상 10층 | 2960446 | 741.5 | 0.195375 | 0.007415 | 0.38075
2960589 | 지상 10층 | 지상 10층 | 2960446 | 716.5 | 0.189125 | 0.007165 | 0.37825
2960590 | 지상 10층 | 지상 10층 | 2960446 | 716.5 | 0.189125 | 0.007165 | 0.37825
2960591 | 지상 10층 | 지상 10층 | 2960446 | 300 | 0.085 | 0.003 | 0.16
2960592 | 지상 10층 | 지상 10층 | 2960446 | 600 | 0.16 | 0.006 | 0.3
2960593 | 지상 10층 | 지상 10층 | 2960446 | 2100 | 0.535 | 0.021 | 1.06
2960598 | 지상 10층 | 지상 10층 | 2960446 | 741.5 | 0.195375 | 0.007415 | 0.38075
2960599 | 지상 10층 | 지상 10층 | 2960446 | 741.5 | 0.195375 | 0.007415 | 0.38075
2960600 | 지상 10층 | 지상 10층 | 2960446 | 716.5 | 0.189125 | 0.007165 | 0.37825
2960601 | 지상 10층 | 지상 10층 | 2960446 | 716.5 | 0.189125 | 0.007165 | 0.37825
2960602 | 지상 10층 | 지상 10층 | 2960446 | 300 | 0.085 | 0.003 | 0.16
2960603 | 지상 10층 | 지상 10층 | 2960446 | 600 | 0.16 | 0.006 | 0.3
2960604 | 지상 10층 | 지상 10층 | 2960446 | 2100 | 0.535 | 0.021 | 1.06
2960609 | 지상 10층 | 지상 10층 | 2960446 | 741.5 | 0.195375 | 0.007415 | 0.38075
2960610 | 지상 10층 | 지상 10층 | 2960446 | 741.5 | 0.195375 | 0.007415 | 0.38075
2960611 | 지상 10층 | 지상 10층 | 2960446 | 716.5 | 0.189125 | 0.007165 | 0.37825
2960612 | 지상 10층 | 지상 10층 | 2960446 | 716.5 | 0.189125 | 0.007165 | 0.37825
2960613 | 지상 10층 | 지상 10층 | 2960446 | 300 | 0.085 | 0.003 | 0.16
2960614 | 지상 10층 | 지상 10층 | 2960446 | 600 | 0.16 | 0.006 | 0.3
2960615 | 지상 10층 | 지상 10층 | 2960446 | 2100 | 0.535 | 0.021 | 1.06
2960620 | 지상 10층 | 지상 10층 | 2960446 | 741.5 | 0.195375 | 0.007415 | 0.38075
2960621 | 지상 10층 | 지상 10층 | 2960446 | 1120 | 0.29 | 0.0112 | 0.58
2960622 | 지상 10층 | 지상 10층 | 2960446 | 1120 | 0.29 | 0.0112 | 0.58
2960623 | 지상 10층 | 지상 10층 | 2960446 | 1120 | 0.29 | 0.0112 | 0.58
2960624 | 지상 10층 | 지상 10층 | 2960446 | 300 | 0.085 | 0.003 | 0.16
2960625 | 지상 10층 | 지상 10층 | 2960446 | 600 | 0.16 | 0.006 | 0.3
2960626 | 지상 10층 | 지상 10층 | 2960446 | 2100 | 0.535 | 0.021 | 1.06
2960631 | 지상 10층 | 지상 10층 | 2960446 | 1120 | 0.29 | 0.0112 | 0.58
2960632 | 지상 10층 | 지상 10층 | 2960446 | 743.357 | 0.195839 | 0.00743357 | 0.381679
2960633 | 지상 10층 | 지상 10층 | 2960446 | 718.357 | 0.189589 | 0.00718357 | 0.379179
2960634 | 지상 10층 | 지상 10층 | 2960446 | 718.357 | 0.189589 | 0.00718357 | 0.379179
2960635 | 지상 10층 | 지상 10층 | 2960446 | 300 | 0.085 | 0.003 | 0.16
2960636 | 지상 10층 | 지상 10층 | 2960446 | 600 | 0.16 | 0.006 | 0.3
2960637 | 지상 10층 | 지상 10층 | 2960446 | 2100 | 0.535 | 0.021 | 1.06
2960642 | 지상 10층 | 지상 10층 | 2960446 | 743.357 | 0.195839 | 0.00743357 | 0.381679
2960643 | 지상 10층 | 지상 10층 | 2960446 | 743.357 | 0.195839 | 0.00743357 | 0.381679
2960644 | 지상 10층 | 지상 10층 | 2960446 | 718.357 | 0.189589 | 0.00718357 | 0.379179
2960645 | 지상 10층 | 지상 10층 | 2960446 | 718.357 | 0.189589 | 0.00718357 | 0.379179
2960646 | 지상 10층 | 지상 10층 | 2960446 | 300 | 0.085 | 0.003 | 0.16
2960647 | 지상 10층 | 지상 10층 | 2960446 | 600 | 0.16 | 0.006 | 0.3
2960648 | 지상 10층 | 지상 10층 | 2960446 | 2100 | 0.535 | 0.021 | 1.06
2960653 | 지상 10층 | 지상 10층 | 2960446 | 743.357 | 0.195839 | 0.00743357 | 0.381679
2960654 | 지상 10층 | 지상 10층 | 2960446 | 743.357 | 0.195839 | 0.00743357 | 0.381679
2960655 | 지상 10층 | 지상 10층 | 2960446 | 718.357 | 0.189589 | 0.00718357 | 0.379179
2960656 | 지상 10층 | 지상 10층 | 2960446 | 718.357 | 0.189589 | 0.00718357 | 0.379179
2960657 | 지상 10층 | 지상 10층 | 2960446 | 300 | 0.085 | 0.003 | 0.16
2960658 | 지상 10층 | 지상 10층 | 2960446 | 600 | 0.16 | 0.006 | 0.3
2960659 | 지상 10층 | 지상 10층 | 2960446 | 2100 | 0.535 | 0.021 | 1.06
2960664 | 지상 10층 | 지상 10층 | 2960446 | 743.357 | 0.195839 | 0.00743357 | 0.381679
2960665 | 지상 10층 | 지상 10층 | 2960446 | 743.357 | 0.195839 | 0.00743357 | 0.381679
2960666 | 지상 10층 | 지상 10층 | 2960446 | 718.357 | 0.189589 | 0.00718357 | 0.379179
2960667 | 지상 10층 | 지상 10층 | 2960446 | 718.357 | 0.189589 | 0.00718357 | 0.379179
2960668 | 지상 10층 | 지상 10층 | 2960446 | 300 | 0.085 | 0.003 | 0.16
2960669 | 지상 10층 | 지상 10층 | 2960446 | 600 | 0.16 | 0.006 | 0.3
2960670 | 지상 10층 | 지상 10층 | 2960446 | 2100 | 0.535 | 0.021 | 1.06
2960675 | 지상 10층 | 지상 10층 | 2960446 | 743.357 | 0.195839 | 0.00743357 | 0.381679
2960676 | 지상 10층 | 지상 10층 | 2960446 | 743.357 | 0.195839 | 0.00743357 | 0.381679
2960677 | 지상 10층 | 지상 10층 | 2960446 | 718.357 | 0.189589 | 0.00718357 | 0.379179
2960678 | 지상 10층 | 지상 10층 | 2960446 | 718.357 | 0.189589 | 0.00718357 | 0.379179
2960679 | 지상 10층 | 지상 10층 | 2960446 | 300 | 0.085 | 0.003 | 0.16
2960680 | 지상 10층 | 지상 10층 | 2960446 | 600 | 0.16 | 0.006 | 0.3
2960681 | 지상 10층 | 지상 10층 | 2960446 | 2100 | 0.535 | 0.021 | 1.06
2960686 | 지상 10층 | 지상 10층 | 2960446 | 743.357 | 0.195839 | 0.00743357 | 0.381679
2960687 | 지상 10층 | 지상 10층 | 2960446 | 743.357 | 0.195839 | 0.00743357 | 0.381679
2960688 | 지상 10층 | 지상 10층 | 2960446 | 718.357 | 0.189589 | 0.00718357 | 0.379179
2960689 | 지상 10층 | 지상 10층 | 2960446 | 718.357 | 0.189589 | 0.00718357 | 0.379179
2960690 | 지상 10층 | 지상 10층 | 2960446 | 300 | 0.085 | 0.003 | 0.16
2960691 | 지상 10층 | 지상 10층 | 2960446 | 600 | 0.16 | 0.006 | 0.3
2960692 | 지상 10층 | 지상 10층 | 2960446 | 2100 | 0.535 | 0.021 | 1.06
2960697 | 지상 10층 | 지상 10층 | 2960446 | 743.357 | 0.195839 | 0.00743357 | 0.381679
2960698 | 지상 10층 | 지상 10층 | 2960446 | 743.357 | 0.195839 | 0.00743357 | 0.381679
2960699 | 지상 10층 | 지상 10층 | 2960446 | 718.357 | 0.189589 | 0.00718357 | 0.379179
2960700 | 지상 10층 | 지상 10층 | 2960446 | 718.357 | 0.189589 | 0.00718357 | 0.379179
2960701 | 지상 10층 | 지상 10층 | 2960446 | 300 | 0.085 | 0.003 | 0.16
2960702 | 지상 10층 | 지상 10층 | 2960446 | 600 | 0.16 | 0.006 | 0.3
2960703 | 지상 10층 | 지상 10층 | 2960446 | 2100 | 0.535 | 0.021 | 1.06
2960708 | 지상 10층 | 지상 10층 | 2960446 | 743.357 | 0.195839 | 0.00743357 | 0.381679
2960709 | 지상 10층 | 지상 10층 | 2960446 | 912.5 | 0.238125 | 0.009125 | 0.47625
2960710 | 지상 10층 | 지상 10층 | 2960446 | 912.5 | 0.238125 | 0.009125 | 0.47625
2960711 | 지상 10층 | 지상 10층 | 2960446 | 912.5 | 0.238125 | 0.009125 | 0.47625
2960712 | 지상 10층 | 지상 10층 | 2960446 | 300 | 0.085 | 0.003 | 0.16
2960713 | 지상 10층 | 지상 10층 | 2960446 | 600 | 0.16 | 0.006 | 0.3
2960714 | 지상 10층 | 지상 10층 | 2960446 | 2100 | 0.535 | 0.021 | 1.06
2960719 | 지상 10층 | 지상 10층 | 2960446 | 828.5 | 0.217125 | 0.008285 | 0.42425
2960720 | 지상 10층 | 지상 10층 | 2960446 | 828.5 | 0.217125 | 0.008285 | 0.42425
2960721 | 지상 10층 | 지상 10층 | 2960446 | 803.5 | 0.210875 | 0.008035 | 0.42175
2960722 | 지상 10층 | 지상 10층 | 2960446 | 803.5 | 0.210875 | 0.008035 | 0.42175
2960723 | 지상 10층 | 지상 10층 | 2960446 | 650 | 0.1725 | 0.0065 | 0.345
2960728 | 지상 10층 | 지상 10층 | 2960446 | 828.5 | 0.217125 | 0.008285 | 0.42425
2960729 | 지상 10층 | 지상 10층 | 2960446 | 828.5 | 0.217125 | 0.008285 | 0.42425
2960730 | 지상 10층 | 지상 10층 | 2960446 | 803.5 | 0.210875 | 0.008035 | 0.42175
2960731 | 지상 10층 | 지상 10층 | 2960446 | 803.5 | 0.210875 | 0.008035 | 0.42175
2960732 | 지상 10층 | 지상 10층 | 2960446 | 650 | 0.1725 | 0.0065 | 0.345
2960737 | 지상 10층 | 지상 10층 | 2960446 | 828.5 | 0.217125 | 0.008285 | 0.42425
2960738 | 지상 10층 | 지상 10층 | 2960446 | 828.5 | 0.217125 | 0.008285 | 0.42425
2960739 | 지상 10층 | 지상 10층 | 2960446 | 803.5 | 0.210875 | 0.008035 | 0.42175
2960740 | 지상 10층 | 지상 10층 | 2960446 | 803.5 | 0.210875 | 0.008035 | 0.42175
2960741 | 지상 10층 | 지상 10층 | 2960446 | 650 | 0.1725 | 0.0065 | 0.345
2960746 | 지상 10층 | 지상 10층 | 2960446 | 828.5 | 0.217125 | 0.008285 | 0.42425
2960747 | 지상 10층 | 지상 10층 | 2960446 | 828.5 | 0.217125 | 0.008285 | 0.42425
2960748 | 지상 10층 | 지상 10층 | 2960446 | 803.5 | 0.210875 | 0.008035 | 0.42175
2960749 | 지상 10층 | 지상 10층 | 2960446 | 803.5 | 0.210875 | 0.008035 | 0.42175
2960750 | 지상 10층 | 지상 10층 | 2960446 | 650 | 0.1725 | 0.0065 | 0.345
2960755 | 지상 10층 | 지상 10층 | 2960446 | 754 | 0.1985 | 0.00754 | 0.387
2960756 | 지상 10층 | 지상 10층 | 2960446 | 754 | 0.1985 | 0.00754 | 0.387
2960757 | 지상 10층 | 지상 10층 | 2960446 | 729 | 0.19225 | 0.00729 | 0.3845
2960758 | 지상 10층 | 지상 10층 | 2960446 | 729 | 0.19225 | 0.00729 | 0.3845
2960759 | 지상 10층 | 지상 10층 | 2960446 | 650 | 0.1725 | 0.0065 | 0.345
2960764 | 지상 10층 | 지상 10층 | 2960446 | 754 | 0.1985 | 0.00754 | 0.387
2960765 | 지상 10층 | 지상 10층 | 2960446 | 754 | 0.1985 | 0.00754 | 0.387
2960766 | 지상 10층 | 지상 10층 | 2960446 | 729 | 0.19225 | 0.00729 | 0.3845
2960767 | 지상 10층 | 지상 10층 | 2960446 | 729 | 0.19225 | 0.00729 | 0.3845
2960768 | 지상 10층 | 지상 10층 | 2960446 | 650 | 0.1725 | 0.0065 | 0.345
2960773 | 지상 10층 | 지상 10층 | 2960446 | 754 | 0.1985 | 0.00754 | 0.387
2960774 | 지상 10층 | 지상 10층 | 2960446 | 754 | 0.1985 | 0.00754 | 0.387
2960775 | 지상 10층 | 지상 10층 | 2960446 | 729 | 0.19225 | 0.00729 | 0.3845
2960776 | 지상 10층 | 지상 10층 | 2960446 | 729 | 0.19225 | 0.00729 | 0.3845
2960777 | 지상 10층 | 지상 10층 | 2960446 | 650 | 0.1725 | 0.0065 | 0.345
2960782 | 지상 10층 | 지상 10층 | 2960446 | 754 | 0.1985 | 0.00754 | 0.387
2960783 | 지상 10층 | 지상 10층 | 2960446 | 754 | 0.1985 | 0.00754 | 0.387
2960784 | 지상 10층 | 지상 10층 | 2960446 | 729 | 0.19225 | 0.00729 | 0.3845
2960785 | 지상 10층 | 지상 10층 | 2960446 | 729 | 0.19225 | 0.00729 | 0.3845
2960786 | 지상 10층 | 지상 10층 | 2960446 | 650 | 0.1725 | 0.0065 | 0.345
2960791 | 지상 10층 | 지상 10층 | 2960446 | 741.5 | 0.195375 | 0.007415 | 0.38075
2960792 | 지상 10층 | 지상 10층 | 2960446 | 741.5 | 0.195375 | 0.007415 | 0.38075
2960793 | 지상 10층 | 지상 10층 | 2960446 | 716.5 | 0.189125 | 0.007165 | 0.37825
2960794 | 지상 10층 | 지상 10층 | 2960446 | 716.5 | 0.189125 | 0.007165 | 0.37825
2960795 | 지상 10층 | 지상 10층 | 2960446 | 650 | 0.1725 | 0.0065 | 0.345
2960800 | 지상 10층 | 지상 10층 | 2960446 | 741.5 | 0.195375 | 0.007415 | 0.38075
2960801 | 지상 10층 | 지상 10층 | 2960446 | 741.5 | 0.195375 | 0.007415 | 0.38075
2960802 | 지상 10층 | 지상 10층 | 2960446 | 716.5 | 0.189125 | 0.007165 | 0.37825
2960803 | 지상 10층 | 지상 10층 | 2960446 | 716.5 | 0.189125 | 0.007165 | 0.37825
2960804 | 지상 10층 | 지상 10층 | 2960446 | 650 | 0.1725 | 0.0065 | 0.345
2960809 | 지상 10층 | 지상 10층 | 2960446 | 741.5 | 0.195375 | 0.007415 | 0.38075
2960810 | 지상 10층 | 지상 10층 | 2960446 | 741.5 | 0.195375 | 0.007415 | 0.38075
2960811 | 지상 10층 | 지상 10층 | 2960446 | 716.5 | 0.189125 | 0.007165 | 0.37825
2960812 | 지상 10층 | 지상 10층 | 2960446 | 716.5 | 0.189125 | 0.007165 | 0.37825
2960813 | 지상 10층 | 지상 10층 | 2960446 | 650 | 0.1725 | 0.0065 | 0.345
2960818 | 지상 10층 | 지상 10층 | 2960446 | 741.5 | 0.195375 | 0.007415 | 0.38075
2960819 | 지상 10층 | 지상 10층 | 2960446 | 741.5 | 0.195375 | 0.007415 | 0.38075
2960820 | 지상 10층 | 지상 10층 | 2960446 | 716.5 | 0.189125 | 0.007165 | 0.37825
2960821 | 지상 10층 | 지상 10층 | 2960446 | 716.5 | 0.189125 | 0.007165 | 0.37825
2960822 | 지상 10층 | 지상 10층 | 2960446 | 650 | 0.1725 | 0.0065 | 0.345
2960827 | 지상 10층 | 지상 10층 | 2960446 | 743.357 | 0.195839 | 0.00743357 | 0.381679
2960828 | 지상 10층 | 지상 10층 | 2960446 | 743.357 | 0.195839 | 0.00743357 | 0.381679
2960829 | 지상 10층 | 지상 10층 | 2960446 | 718.357 | 0.189589 | 0.00718357 | 0.379179
2960830 | 지상 10층 | 지상 10층 | 2960446 | 718.357 | 0.189589 | 0.00718357 | 0.379179
2960831 | 지상 10층 | 지상 10층 | 2960446 | 650 | 0.1725 | 0.0065 | 0.345
2960836 | 지상 10층 | 지상 10층 | 2960446 | 743.357 | 0.195839 | 0.00743357 | 0.381679
2960837 | 지상 10층 | 지상 10층 | 2960446 | 743.357 | 0.195839 | 0.00743357 | 0.381679
2960838 | 지상 10층 | 지상 10층 | 2960446 | 718.357 | 0.189589 | 0.00718357 | 0.379179
2960839 | 지상 10층 | 지상 10층 | 2960446 | 718.357 | 0.189589 | 0.00718357 | 0.379179
2960840 | 지상 10층 | 지상 10층 | 2960446 | 650 | 0.1725 | 0.0065 | 0.345
2960845 | 지상 10층 | 지상 10층 | 2960446 | 743.357 | 0.195839 | 0.00743357 | 0.381679
2960846 | 지상 10층 | 지상 10층 | 2960446 | 743.357 | 0.195839 | 0.00743357 | 0.381679
2960847 | 지상 10층 | 지상 10층 | 2960446 | 718.357 | 0.189589 | 0.00718357 | 0.379179
2960848 | 지상 10층 | 지상 10층 | 2960446 | 718.357 | 0.189589 | 0.00718357 | 0.379179
2960849 | 지상 10층 | 지상 10층 | 2960446 | 650 | 0.1725 | 0.0065 | 0.345
2960854 | 지상 10층 | 지상 10층 | 2960446 | 743.357 | 0.195839 | 0.00743357 | 0.381679
2960855 | 지상 10층 | 지상 10층 | 2960446 | 743.357 | 0.195839 | 0.00743357 | 0.381679
2960856 | 지상 10층 | 지상 10층 | 2960446 | 718.357 | 0.189589 | 0.00718357 | 0.379179
2960857 | 지상 10층 | 지상 10층 | 2960446 | 718.357 | 0.189589 | 0.00718357 | 0.379179
2960858 | 지상 10층 | 지상 10층 | 2960446 | 650 | 0.1725 | 0.0065 | 0.345
2960863 | 지상 10층 | 지상 10층 | 2960446 | 743.357 | 0.195839 | 0.00743357 | 0.381679
2960864 | 지상 10층 | 지상 10층 | 2960446 | 743.357 | 0.195839 | 0.00743357 | 0.381679
2960865 | 지상 10층 | 지상 10층 | 2960446 | 718.357 | 0.189589 | 0.00718357 | 0.379179
2960866 | 지상 10층 | 지상 10층 | 2960446 | 718.357 | 0.189589 | 0.00718357 | 0.379179
2960867 | 지상 10층 | 지상 10층 | 2960446 | 650 | 0.1725 | 0.0065 | 0.345
2960872 | 지상 10층 | 지상 10층 | 2960446 | 743.357 | 0.195839 | 0.00743357 | 0.381679
2960873 | 지상 10층 | 지상 10층 | 2960446 | 743.357 | 0.195839 | 0.00743357 | 0.381679
2960874 | 지상 10층 | 지상 10층 | 2960446 | 718.357 | 0.189589 | 0.00718357 | 0.379179
2960875 | 지상 10층 | 지상 10층 | 2960446 | 718.357 | 0.189589 | 0.00718357 | 0.379179
2960876 | 지상 10층 | 지상 10층 | 2960446 | 650 | 0.1725 | 0.0065 | 0.345
2960881 | 지상 10층 | 지상 10층 | 2960446 | 743.357 | 0.195839 | 0.00743357 | 0.381679
2960882 | 지상 10층 | 지상 10층 | 2960446 | 743.357 | 0.195839 | 0.00743357 | 0.381679
2960883 | 지상 10층 | 지상 10층 | 2960446 | 718.357 | 0.189589 | 0.00718357 | 0.379179
2960884 | 지상 10층 | 지상 10층 | 2960446 | 718.357 | 0.189589 | 0.00718357 | 0.379179
2960885 | 지상 10층 | 지상 10층 | 2960446 | 650 | 0.1725 | 0.0065 | 0.345
2970487 | 지상 10층 | 지상 10층 | 2970485 | 892.928 | 0.233232 | 0.00892928 | 0.466464
2970488 | 지상 10층 | 지상 10층 | 2970485 | 912.816 | 0.238204 | 0.00912816 | 0.476408
2970495 | 지상 10층 | 지상 10층 | 2970485 | 912.816 | 0.238204 | 0.00912816 | 0.476408
2970500 | 지상 10층 | 지상 10층 | 2970485 | 912.816 | 0.238204 | 0.00912816 | 0.476408
2970505 | 지상 10층 | 지상 10층 | 2970485 | 912.816 | 0.238204 | 0.00912816 | 0.476408
2970506 | 지상 10층 | 지상 10층 | 2970485 | 970 | 0.2525 | 0.0097 | 0.495
2970507 | 지상 10층 | 지상 10층 | 2970485 | 945 | 0.24625 | 0.00945 | 0.4925
2970508 | 지상 10층 | 지상 10층 | 2970485 | 945 | 0.24625 | 0.00945 | 0.4925
2970509 | 지상 10층 | 지상 10층 | 2970485 | 300 | 0.085 | 0.003 | 0.16
2970510 | 지상 10층 | 지상 10층 | 2970485 | 600 | 0.16 | 0.006 | 0.3
2970511 | 지상 10층 | 지상 10층 | 2970485 | 2100 | 0.535 | 0.021 | 1.06
2970516 | 지상 10층 | 지상 10층 | 2970485 | 940 | 0.245 | 0.0094 | 0.48
2970517 | 지상 10층 | 지상 10층 | 2970485 | 940 | 0.245 | 0.0094 | 0.48
2970518 | 지상 10층 | 지상 10층 | 2970485 | 915 | 0.23875 | 0.00915 | 0.4775
2970519 | 지상 10층 | 지상 10층 | 2970485 | 915 | 0.23875 | 0.00915 | 0.4775
2970520 | 지상 10층 | 지상 10층 | 2970485 | 300 | 0.085 | 0.003 | 0.16
2970521 | 지상 10층 | 지상 10층 | 2970485 | 600 | 0.16 | 0.006 | 0.3
2970522 | 지상 10층 | 지상 10층 | 2970485 | 2100 | 0.535 | 0.021 | 1.06
2970527 | 지상 10층 | 지상 10층 | 2970485 | 940 | 0.245 | 0.0094 | 0.48
2970528 | 지상 10층 | 지상 10층 | 2970485 | 940 | 0.245 | 0.0094 | 0.48
2970529 | 지상 10층 | 지상 10층 | 2970485 | 915 | 0.23875 | 0.00915 | 0.4775
2970530 | 지상 10층 | 지상 10층 | 2970485 | 915 | 0.23875 | 0.00915 | 0.4775
2970531 | 지상 10층 | 지상 10층 | 2970485 | 300 | 0.085 | 0.003 | 0.16
2970532 | 지상 10층 | 지상 10층 | 2970485 | 600 | 0.16 | 0.006 | 0.3
2970533 | 지상 10층 | 지상 10층 | 2970485 | 2100 | 0.535 | 0.021 | 1.06
2970538 | 지상 10층 | 지상 10층 | 2970485 | 940 | 0.245 | 0.0094 | 0.48
2970539 | 지상 10층 | 지상 10층 | 2970485 | 940 | 0.245 | 0.0094 | 0.48
2970540 | 지상 10층 | 지상 10층 | 2970485 | 915 | 0.23875 | 0.00915 | 0.4775
2970541 | 지상 10층 | 지상 10층 | 2970485 | 915 | 0.23875 | 0.00915 | 0.4775
2970542 | 지상 10층 | 지상 10층 | 2970485 | 300 | 0.085 | 0.003 | 0.16
2970543 | 지상 10층 | 지상 10층 | 2970485 | 600 | 0.16 | 0.006 | 0.3
2970544 | 지상 10층 | 지상 10층 | 2970485 | 2100 | 0.535 | 0.021 | 1.06
2970549 | 지상 10층 | 지상 10층 | 2970485 | 940 | 0.245 | 0.0094 | 0.48
2970550 | 지상 10층 | 지상 10층 | 2970485 | 940 | 0.245 | 0.0094 | 0.48
2970551 | 지상 10층 | 지상 10층 | 2970485 | 915 | 0.23875 | 0.00915 | 0.4775
2970552 | 지상 10층 | 지상 10층 | 2970485 | 915 | 0.23875 | 0.00915 | 0.4775
2970553 | 지상 10층 | 지상 10층 | 2970485 | 300 | 0.085 | 0.003 | 0.16
2970554 | 지상 10층 | 지상 10층 | 2970485 | 600 | 0.16 | 0.006 | 0.3
2970555 | 지상 10층 | 지상 10층 | 2970485 | 2100 | 0.535 | 0.021 | 1.06
2970560 | 지상 10층 | 지상 10층 | 2970485 | 940 | 0.245 | 0.0094 | 0.48
2970561 | 지상 10층 | 지상 10층 | 2970485 | 940 | 0.245 | 0.0094 | 0.48
2970562 | 지상 10층 | 지상 10층 | 2970485 | 915 | 0.23875 | 0.00915 | 0.4775
2970563 | 지상 10층 | 지상 10층 | 2970485 | 915 | 0.23875 | 0.00915 | 0.4775
2970564 | 지상 10층 | 지상 10층 | 2970485 | 300 | 0.085 | 0.003 | 0.16
2970565 | 지상 10층 | 지상 10층 | 2970485 | 600 | 0.16 | 0.006 | 0.3
2970566 | 지상 10층 | 지상 10층 | 2970485 | 2100 | 0.535 | 0.021 | 1.06
2970571 | 지상 10층 | 지상 10층 | 2970485 | 970 | 0.2525 | 0.0097 | 0.495
2970572 | 지상 10층 | 지상 10층 | 2970485 | 1010 | 0.2625 | 0.0101 | 0.525
2970573 | 지상 10층 | 지상 10층 | 2970485 | 1010 | 0.2625 | 0.0101 | 0.525
2970574 | 지상 10층 | 지상 10층 | 2970485 | 1010 | 0.2625 | 0.0101 | 0.525
2970575 | 지상 10층 | 지상 10층 | 2970485 | 300 | 0.085 | 0.003 | 0.16
2970576 | 지상 10층 | 지상 10층 | 2970485 | 600 | 0.16 | 0.006 | 0.3
2970577 | 지상 10층 | 지상 10층 | 2970485 | 2100 | 0.535 | 0.021 | 1.06
2970582 | 지상 10층 | 지상 10층 | 2970485 | 1010 | 0.2625 | 0.0101 | 0.525
2970583 | 지상 10층 | 지상 10층 | 2970485 | 1080 | 0.28 | 0.0108 | 0.55
2970584 | 지상 10층 | 지상 10층 | 2970485 | 1055 | 0.27375 | 0.01055 | 0.5475
2970585 | 지상 10층 | 지상 10층 | 2970485 | 1055 | 0.27375 | 0.01055 | 0.5475
2970586 | 지상 10층 | 지상 10층 | 2970485 | 300 | 0.085 | 0.003 | 0.16
2970587 | 지상 10층 | 지상 10층 | 2970485 | 600 | 0.16 | 0.006 | 0.3
2970588 | 지상 10층 | 지상 10층 | 2970485 | 2100 | 0.535 | 0.021 | 1.06
2970593 | 지상 10층 | 지상 10층 | 2970485 | 1110 | 0.2875 | 0.0111 | 0.565
2970594 | 지상 10층 | 지상 10층 | 2970485 | 1010 | 0.2625 | 0.0101 | 0.525
2970595 | 지상 10층 | 지상 10층 | 2970485 | 1010 | 0.2625 | 0.0101 | 0.525
2970596 | 지상 10층 | 지상 10층 | 2970485 | 1010 | 0.2625 | 0.0101 | 0.525
2970597 | 지상 10층 | 지상 10층 | 2970485 | 300 | 0.085 | 0.003 | 0.16
2970598 | 지상 10층 | 지상 10층 | 2970485 | 600 | 0.16 | 0.006 | 0.3
2970599 | 지상 10층 | 지상 10층 | 2970485 | 2100 | 0.535 | 0.021 | 1.06
2970604 | 지상 10층 | 지상 10층 | 2970485 | 1010 | 0.2625 | 0.0101 | 0.525
2970605 | 지상 10층 | 지상 10층 | 2970485 | 940 | 0.245 | 0.0094 | 0.48
2970606 | 지상 10층 | 지상 10층 | 2970485 | 915 | 0.23875 | 0.00915 | 0.4775
2970607 | 지상 10층 | 지상 10층 | 2970485 | 915 | 0.23875 | 0.00915 | 0.4775
2970608 | 지상 10층 | 지상 10층 | 2970485 | 300 | 0.085 | 0.003 | 0.16
2970609 | 지상 10층 | 지상 10층 | 2970485 | 600 | 0.16 | 0.006 | 0.3
2970610 | 지상 10층 | 지상 10층 | 2970485 | 2100 | 0.535 | 0.021 | 1.06
2970615 | 지상 10층 | 지상 10층 | 2970485 | 940 | 0.245 | 0.0094 | 0.48
2970616 | 지상 10층 | 지상 10층 | 2970485 | 940 | 0.245 | 0.0094 | 0.48
2970617 | 지상 10층 | 지상 10층 | 2970485 | 915 | 0.23875 | 0.00915 | 0.4775
2970618 | 지상 10층 | 지상 10층 | 2970485 | 915 | 0.23875 | 0.00915 | 0.4775
2970619 | 지상 10층 | 지상 10층 | 2970485 | 300 | 0.085 | 0.003 | 0.16
2970620 | 지상 10층 | 지상 10층 | 2970485 | 600 | 0.16 | 0.006 | 0.3
2970621 | 지상 10층 | 지상 10층 | 2970485 | 2100 | 0.535 | 0.021 | 1.06
2970626 | 지상 10층 | 지상 10층 | 2970485 | 940 | 0.245 | 0.0094 | 0.48
2970627 | 지상 10층 | 지상 10층 | 2970485 | 940 | 0.245 | 0.0094 | 0.48
2970628 | 지상 10층 | 지상 10층 | 2970485 | 915 | 0.23875 | 0.00915 | 0.4775
2970629 | 지상 10층 | 지상 10층 | 2970485 | 915 | 0.23875 | 0.00915 | 0.4775
2970630 | 지상 10층 | 지상 10층 | 2970485 | 300 | 0.085 | 0.003 | 0.16
2970631 | 지상 10층 | 지상 10층 | 2970485 | 600 | 0.16 | 0.006 | 0.3
2970632 | 지상 10층 | 지상 10층 | 2970485 | 2100 | 0.535 | 0.021 | 1.06
2970637 | 지상 10층 | 지상 10층 | 2970485 | 940 | 0.245 | 0.0094 | 0.48
2970638 | 지상 10층 | 지상 10층 | 2970485 | 940 | 0.245 | 0.0094 | 0.48
2970639 | 지상 10층 | 지상 10층 | 2970485 | 915 | 0.23875 | 0.00915 | 0.4775
2970640 | 지상 10층 | 지상 10층 | 2970485 | 915 | 0.23875 | 0.00915 | 0.4775
2970641 | 지상 10층 | 지상 10층 | 2970485 | 300 | 0.085 | 0.003 | 0.16
2970642 | 지상 10층 | 지상 10층 | 2970485 | 600 | 0.16 | 0.006 | 0.3
2970643 | 지상 10층 | 지상 10층 | 2970485 | 2100 | 0.535 | 0.021 | 1.06
2970648 | 지상 10층 | 지상 10층 | 2970485 | 940 | 0.245 | 0.0094 | 0.48
2970649 | 지상 10층 | 지상 10층 | 2970485 | 940 | 0.245 | 0.0094 | 0.48
2970650 | 지상 10층 | 지상 10층 | 2970485 | 915 | 0.23875 | 0.00915 | 0.4775
2970651 | 지상 10층 | 지상 10층 | 2970485 | 915 | 0.23875 | 0.00915 | 0.4775
2970652 | 지상 10층 | 지상 10층 | 2970485 | 300 | 0.085 | 0.003 | 0.16
2970653 | 지상 10층 | 지상 10층 | 2970485 | 600 | 0.16 | 0.006 | 0.3
2970654 | 지상 10층 | 지상 10층 | 2970485 | 2100 | 0.535 | 0.021 | 1.06
2970659 | 지상 10층 | 지상 10층 | 2970485 | 935 | 0.24375 | 0.00935 | 0.4775
2970660 | 지상 10층 | 지상 10층 | 2970485 | 1010 | 0.2625 | 0.0101 | 0.525
2970661 | 지상 10층 | 지상 10층 | 2970485 | 1010 | 0.2625 | 0.0101 | 0.525
2970662 | 지상 10층 | 지상 10층 | 2970485 | 1010 | 0.2625 | 0.0101 | 0.525
2970663 | 지상 10층 | 지상 10층 | 2970485 | 300 | 0.085 | 0.003 | 0.16
2970664 | 지상 10층 | 지상 10층 | 2970485 | 600 | 0.16 | 0.006 | 0.3
2970665 | 지상 10층 | 지상 10층 | 2970485 | 2100 | 0.535 | 0.021 | 1.06
2970670 | 지상 10층 | 지상 10층 | 2970485 | 1010 | 0.2625 | 0.0101 | 0.525
2970671 | 지상 10층 | 지상 10층 | 2970485 | 995 | 0.25875 | 0.00995 | 0.5075
2970672 | 지상 10층 | 지상 10층 | 2970485 | 970 | 0.2525 | 0.0097 | 0.505
2970673 | 지상 10층 | 지상 10층 | 2970485 | 970 | 0.2525 | 0.0097 | 0.505
2970674 | 지상 10층 | 지상 10층 | 2970485 | 300 | 0.085 | 0.003 | 0.16
2970675 | 지상 10층 | 지상 10층 | 2970485 | 600 | 0.16 | 0.006 | 0.3
2970676 | 지상 10층 | 지상 10층 | 2970485 | 2100 | 0.535 | 0.021 | 1.06
2970681 | 지상 10층 | 지상 10층 | 2970485 | 940 | 0.245 | 0.0094 | 0.48
2970682 | 지상 10층 | 지상 10층 | 2970485 | 940 | 0.245 | 0.0094 | 0.48
2970683 | 지상 10층 | 지상 10층 | 2970485 | 915 | 0.23875 | 0.00915 | 0.4775
2970684 | 지상 10층 | 지상 10층 | 2970485 | 915 | 0.23875 | 0.00915 | 0.4775
2970685 | 지상 10층 | 지상 10층 | 2970485 | 300 | 0.085 | 0.003 | 0.16
2970686 | 지상 10층 | 지상 10층 | 2970485 | 600 | 0.16 | 0.006 | 0.3
2970687 | 지상 10층 | 지상 10층 | 2970485 | 2100 | 0.535 | 0.021 | 1.06
2970692 | 지상 10층 | 지상 10층 | 2970485 | 940 | 0.245 | 0.0094 | 0.48
2970693 | 지상 10층 | 지상 10층 | 2970485 | 940 | 0.245 | 0.0094 | 0.48
2970694 | 지상 10층 | 지상 10층 | 2970485 | 915 | 0.23875 | 0.00915 | 0.4775
2970695 | 지상 10층 | 지상 10층 | 2970485 | 915 | 0.23875 | 0.00915 | 0.4775
2970696 | 지상 10층 | 지상 10층 | 2970485 | 300 | 0.085 | 0.003 | 0.16
2970697 | 지상 10층 | 지상 10층 | 2970485 | 600 | 0.16 | 0.006 | 0.3
2970698 | 지상 10층 | 지상 10층 | 2970485 | 2100 | 0.535 | 0.021 | 1.06
2970703 | 지상 10층 | 지상 10층 | 2970485 | 940 | 0.245 | 0.0094 | 0.48
2970704 | 지상 10층 | 지상 10층 | 2970485 | 940 | 0.245 | 0.0094 | 0.48
2970705 | 지상 10층 | 지상 10층 | 2970485 | 915 | 0.23875 | 0.00915 | 0.4775
2970706 | 지상 10층 | 지상 10층 | 2970485 | 915 | 0.23875 | 0.00915 | 0.4775
2970707 | 지상 10층 | 지상 10층 | 2970485 | 300 | 0.085 | 0.003 | 0.16
2970708 | 지상 10층 | 지상 10층 | 2970485 | 600 | 0.16 | 0.006 | 0.3
2970709 | 지상 10층 | 지상 10층 | 2970485 | 2100 | 0.535 | 0.021 | 1.06
2970714 | 지상 10층 | 지상 10층 | 2970485 | 940 | 0.245 | 0.0094 | 0.48
2970715 | 지상 10층 | 지상 10층 | 2970485 | 1015 | 0.26375 | 0.01015 | 0.5275
2970716 | 지상 10층 | 지상 10층 | 2970485 | 1015 | 0.26375 | 0.01015 | 0.5275
2970717 | 지상 10층 | 지상 10층 | 2970485 | 1015 | 0.26375 | 0.01015 | 0.5275
2970718 | 지상 10층 | 지상 10층 | 2970485 | 300 | 0.085 | 0.003 | 0.16
2970719 | 지상 10층 | 지상 10층 | 2970485 | 600 | 0.16 | 0.006 | 0.3
2970720 | 지상 10층 | 지상 10층 | 2970485 | 2100 | 0.535 | 0.021 | 1.06
2970725 | 지상 10층 | 지상 10층 | 2970485 | 1015 | 0.26375 | 0.01015 | 0.5275
2970726 | 지상 10층 | 지상 10층 | 2970485 | 892.928 | 0.233232 | 0.00892928 | 0.466464
2970727 | 지상 10층 | 지상 10층 | 2970485 | 892.928 | 0.233232 | 0.00892928 | 0.466464
2970728 | 지상 10층 | 지상 10층 | 2970485 | 892.928 | 0.233232 | 0.00892928 | 0.466464
2970729 | 지상 10층 | 지상 10층 | 2970485 | 300 | 0.085 | 0.003 | 0.16
2970730 | 지상 10층 | 지상 10층 | 2970485 | 600 | 0.16 | 0.006 | 0.3
2970731 | 지상 10층 | 지상 10층 | 2970485 | 2100 | 0.535 | 0.021 | 1.06
2970736 | 지상 10층 | 지상 10층 | 2970485 | 970 | 0.2525 | 0.0097 | 0.495
2970737 | 지상 10층 | 지상 10층 | 2970485 | 940 | 0.245 | 0.0094 | 0.48
2970738 | 지상 10층 | 지상 10층 | 2970485 | 915 | 0.23875 | 0.00915 | 0.4775
2970739 | 지상 10층 | 지상 10층 | 2970485 | 915 | 0.23875 | 0.00915 | 0.4775
2970740 | 지상 10층 | 지상 10층 | 2970485 | 650 | 0.1725 | 0.0065 | 0.345
2970745 | 지상 10층 | 지상 10층 | 2970485 | 940 | 0.245 | 0.0094 | 0.48
2970746 | 지상 10층 | 지상 10층 | 2970485 | 915 | 0.23875 | 0.00915 | 0.4775
2970747 | 지상 10층 | 지상 10층 | 2970485 | 915 | 0.23875 | 0.00915 | 0.4775
2970748 | 지상 10층 | 지상 10층 | 2970485 | 940 | 0.245 | 0.0094 | 0.48
2970749 | 지상 10층 | 지상 10층 | 2970485 | 650 | 0.1725 | 0.0065 | 0.345
2970754 | 지상 10층 | 지상 10층 | 2970485 | 940 | 0.245 | 0.0094 | 0.48
2970755 | 지상 10층 | 지상 10층 | 2970485 | 915 | 0.23875 | 0.00915 | 0.4775
2970756 | 지상 10층 | 지상 10층 | 2970485 | 915 | 0.23875 | 0.00915 | 0.4775
2970757 | 지상 10층 | 지상 10층 | 2970485 | 940 | 0.245 | 0.0094 | 0.48
2970758 | 지상 10층 | 지상 10층 | 2970485 | 650 | 0.1725 | 0.0065 | 0.345
2970763 | 지상 10층 | 지상 10층 | 2970485 | 940 | 0.245 | 0.0094 | 0.48
2970764 | 지상 10층 | 지상 10층 | 2970485 | 915 | 0.23875 | 0.00915 | 0.4775
2970765 | 지상 10층 | 지상 10층 | 2970485 | 915 | 0.23875 | 0.00915 | 0.4775
2970766 | 지상 10층 | 지상 10층 | 2970485 | 940 | 0.245 | 0.0094 | 0.48
2970767 | 지상 10층 | 지상 10층 | 2970485 | 650 | 0.1725 | 0.0065 | 0.345
2970772 | 지상 10층 | 지상 10층 | 2970485 | 940 | 0.245 | 0.0094 | 0.48
2970773 | 지상 10층 | 지상 10층 | 2970485 | 915 | 0.23875 | 0.00915 | 0.4775
2970774 | 지상 10층 | 지상 10층 | 2970485 | 915 | 0.23875 | 0.00915 | 0.4775
2970775 | 지상 10층 | 지상 10층 | 2970485 | 940 | 0.245 | 0.0094 | 0.48
2970776 | 지상 10층 | 지상 10층 | 2970485 | 650 | 0.1725 | 0.0065 | 0.345
2970781 | 지상 10층 | 지상 10층 | 2970485 | 970 | 0.2525 | 0.0097 | 0.495
2970782 | 지상 10층 | 지상 10층 | 2970485 | 945 | 0.24625 | 0.00945 | 0.4925
2970783 | 지상 10층 | 지상 10층 | 2970485 | 945 | 0.24625 | 0.00945 | 0.4925
2970784 | 지상 10층 | 지상 10층 | 2970485 | 940 | 0.245 | 0.0094 | 0.48
2970785 | 지상 10층 | 지상 10층 | 2970485 | 650 | 0.1725 | 0.0065 | 0.345
2970790 | 지상 10층 | 지상 10층 | 2970485 | 1110 | 0.2875 | 0.0111 | 0.565
2970791 | 지상 10층 | 지상 10층 | 2970485 | 1085.02 | 0.281254 | 0.0108502 | 0.562508
2970792 | 지상 10층 | 지상 10층 | 2970485 | 1085.02 | 0.281254 | 0.0108502 | 0.562508
2970793 | 지상 10층 | 지상 10층 | 2970485 | 1080 | 0.28 | 0.0108 | 0.55
2970794 | 지상 10층 | 지상 10층 | 2970485 | 650 | 0.1725 | 0.0065 | 0.345
2970799 | 지상 10층 | 지상 10층 | 2970485 | 940 | 0.245 | 0.0094 | 0.48
2970800 | 지상 10층 | 지상 10층 | 2970485 | 915 | 0.23875 | 0.00915 | 0.4775
2970801 | 지상 10층 | 지상 10층 | 2970485 | 915 | 0.23875 | 0.00915 | 0.4775
2970802 | 지상 10층 | 지상 10층 | 2970485 | 940 | 0.245 | 0.0094 | 0.48
2970803 | 지상 10층 | 지상 10층 | 2970485 | 650 | 0.1725 | 0.0065 | 0.345
2970808 | 지상 10층 | 지상 10층 | 2970485 | 940 | 0.245 | 0.0094 | 0.48
2970809 | 지상 10층 | 지상 10층 | 2970485 | 915 | 0.23875 | 0.00915 | 0.4775
2970810 | 지상 10층 | 지상 10층 | 2970485 | 915 | 0.23875 | 0.00915 | 0.4775
2970811 | 지상 10층 | 지상 10층 | 2970485 | 940 | 0.245 | 0.0094 | 0.48
2970812 | 지상 10층 | 지상 10층 | 2970485 | 650 | 0.1725 | 0.0065 | 0.345
2970817 | 지상 10층 | 지상 10층 | 2970485 | 940 | 0.245 | 0.0094 | 0.48
2970818 | 지상 10층 | 지상 10층 | 2970485 | 915 | 0.23875 | 0.00915 | 0.4775
2970819 | 지상 10층 | 지상 10층 | 2970485 | 915 | 0.23875 | 0.00915 | 0.4775
2970820 | 지상 10층 | 지상 10층 | 2970485 | 940 | 0.245 | 0.0094 | 0.48
2970821 | 지상 10층 | 지상 10층 | 2970485 | 650 | 0.1725 | 0.0065 | 0.345
2970826 | 지상 10층 | 지상 10층 | 2970485 | 940 | 0.245 | 0.0094 | 0.48
2970827 | 지상 10층 | 지상 10층 | 2970485 | 915 | 0.23875 | 0.00915 | 0.4775
2970828 | 지상 10층 | 지상 10층 | 2970485 | 915 | 0.23875 | 0.00915 | 0.4775
2970829 | 지상 10층 | 지상 10층 | 2970485 | 940 | 0.245 | 0.0094 | 0.48
2970830 | 지상 10층 | 지상 10층 | 2970485 | 650 | 0.1725 | 0.0065 | 0.345
2970835 | 지상 10층 | 지상 10층 | 2970485 | 935 | 0.24375 | 0.00935 | 0.4775
2970836 | 지상 10층 | 지상 10층 | 2970485 | 910 | 0.2375 | 0.0091 | 0.475
2970837 | 지상 10층 | 지상 10층 | 2970485 | 910 | 0.2375 | 0.0091 | 0.475
2970838 | 지상 10층 | 지상 10층 | 2970485 | 940 | 0.245 | 0.0094 | 0.48
2970839 | 지상 10층 | 지상 10층 | 2970485 | 650 | 0.1725 | 0.0065 | 0.345
2970844 | 지상 10층 | 지상 10층 | 2970485 | 940 | 0.245 | 0.0094 | 0.48
2970845 | 지상 10층 | 지상 10층 | 2970485 | 915 | 0.23875 | 0.00915 | 0.4775
2970846 | 지상 10층 | 지상 10층 | 2970485 | 915 | 0.23875 | 0.00915 | 0.4775
2970847 | 지상 10층 | 지상 10층 | 2970485 | 995 | 0.25875 | 0.00995 | 0.5075
2970848 | 지상 10층 | 지상 10층 | 2970485 | 650 | 0.1725 | 0.0065 | 0.345
2970853 | 지상 10층 | 지상 10층 | 2970485 | 940 | 0.245 | 0.0094 | 0.48
2970854 | 지상 10층 | 지상 10층 | 2970485 | 915 | 0.23875 | 0.00915 | 0.4775
2970855 | 지상 10층 | 지상 10층 | 2970485 | 915 | 0.23875 | 0.00915 | 0.4775
2970856 | 지상 10층 | 지상 10층 | 2970485 | 940 | 0.245 | 0.0094 | 0.48
2970857 | 지상 10층 | 지상 10층 | 2970485 | 650 | 0.1725 | 0.0065 | 0.345
2970862 | 지상 10층 | 지상 10층 | 2970485 | 940 | 0.245 | 0.0094 | 0.48
2970863 | 지상 10층 | 지상 10층 | 2970485 | 915 | 0.23875 | 0.00915 | 0.4775
2970864 | 지상 10층 | 지상 10층 | 2970485 | 915 | 0.23875 | 0.00915 | 0.4775
2970865 | 지상 10층 | 지상 10층 | 2970485 | 940 | 0.245 | 0.0094 | 0.48
2970866 | 지상 10층 | 지상 10층 | 2970485 | 650 | 0.1725 | 0.0065 | 0.345
2970871 | 지상 10층 | 지상 10층 | 2970485 | 940 | 0.245 | 0.0094 | 0.48
2970872 | 지상 10층 | 지상 10층 | 2970485 | 915 | 0.23875 | 0.00915 | 0.4775
2970873 | 지상 10층 | 지상 10층 | 2970485 | 915 | 0.23875 | 0.00915 | 0.4775
2970874 | 지상 10층 | 지상 10층 | 2970485 | 940 | 0.245 | 0.0094 | 0.48
2970875 | 지상 10층 | 지상 10층 | 2970485 | 650 | 0.1725 | 0.0065 | 0.345
2971243 | 지상 5층 | 지상 5층 | 2971239 | 1025 | 0.26625 | 0.01025 | 0.5325
2971244 | 지상 5층 | 지상 5층 | 2971239 | 913.84 | 0.23846 | 0.0091384 | 0.46692
2971246 | 지상 5층 | 지상 5층 | 2971239 | 1100 | 0.285 | 0.011 | 0.56
2971606 | 지상 5층 | 지상 5층 | 2971239 | 300 | 0.085 | 0.003 | 0.16
2971607 | 지상 5층 | 지상 5층 | 2971239 | 888.84 | 0.23221 | 0.0088884 | 0.46442
2971753 | 지상 5층 | 지상 5층 | 2971239 | 600 | 0.16 | 0.006 | 0.3
2971754 | 지상 5층 | 지상 5층 | 2971239 | 888.84 | 0.23221 | 0.0088884 | 0.46442
2971969 | 지상 5층 | 지상 5층 | 2971239 | 730.972 | 0.192743 | 0.00730972 | 0.375486
2971970 | 지상 5층 | 지상 5층 | 2971239 | 1025 | 0.26625 | 0.01025 | 0.5325
2971971 | 지상 5층 | 지상 5층 | 2971239 | 1025 | 0.26625 | 0.01025 | 0.5325
2971972 | 지상 5층 | 지상 5층 | 2971239 | 1025 | 0.26625 | 0.01025 | 0.5325
2971973 | 지상 5층 | 지상 5층 | 2971239 | 300 | 0.085 | 0.003 | 0.16
2971974 | 지상 5층 | 지상 5층 | 2971239 | 600 | 0.16 | 0.006 | 0.3
2971975 | 지상 5층 | 지상 5층 | 2971239 | 1100 | 0.285 | 0.011 | 0.56
2972389 | 지상 5층 | 지상 5층 | 2971239 | 730.972 | 0.192743 | 0.00730972 | 0.375486
2972390 | 지상 5층 | 지상 5층 | 2971239 | 730.972 | 0.192743 | 0.00730972 | 0.375486
2972391 | 지상 5층 | 지상 5층 | 2971239 | 705.972 | 0.186493 | 0.00705972 | 0.372986
2972392 | 지상 5층 | 지상 5층 | 2971239 | 705.972 | 0.186493 | 0.00705972 | 0.372986
2972393 | 지상 5층 | 지상 5층 | 2971239 | 300 | 0.085 | 0.003 | 0.16
2972394 | 지상 5층 | 지상 5층 | 2971239 | 600 | 0.16 | 0.006 | 0.3
2972395 | 지상 5층 | 지상 5층 | 2971239 | 1100 | 0.285 | 0.011 | 0.56
2972486 | 지상 5층 | 지상 5층 | 2971239 | 730.972 | 0.192743 | 0.00730972 | 0.375486
2972487 | 지상 5층 | 지상 5층 | 2971239 | 730.972 | 0.192743 | 0.00730972 | 0.375486
2972488 | 지상 5층 | 지상 5층 | 2971239 | 705.972 | 0.186493 | 0.00705972 | 0.372986
2972489 | 지상 5층 | 지상 5층 | 2971239 | 705.972 | 0.186493 | 0.00705972 | 0.372986
2972490 | 지상 5층 | 지상 5층 | 2971239 | 300 | 0.085 | 0.003 | 0.16
2972491 | 지상 5층 | 지상 5층 | 2971239 | 600 | 0.16 | 0.006 | 0.3
2972492 | 지상 5층 | 지상 5층 | 2971239 | 1100 | 0.285 | 0.011 | 0.56
2972581 | 지상 5층 | 지상 5층 | 2971239 | 730.972 | 0.192743 | 0.00730972 | 0.375486
2972582 | 지상 5층 | 지상 5층 | 2971239 | 730.972 | 0.192743 | 0.00730972 | 0.375486
2972583 | 지상 5층 | 지상 5층 | 2971239 | 705.972 | 0.186493 | 0.00705972 | 0.372986
2972584 | 지상 5층 | 지상 5층 | 2971239 | 705.972 | 0.186493 | 0.00705972 | 0.372986
2972585 | 지상 5층 | 지상 5층 | 2971239 | 300 | 0.085 | 0.003 | 0.16
2972586 | 지상 5층 | 지상 5층 | 2971239 | 600 | 0.16 | 0.006 | 0.3
2972587 | 지상 5층 | 지상 5층 | 2971239 | 1100 | 0.285 | 0.011 | 0.56
2972675 | 지상 5층 | 지상 5층 | 2971239 | 730.972 | 0.192743 | 0.00730972 | 0.375486
2972676 | 지상 5층 | 지상 5층 | 2971239 | 730.972 | 0.192743 | 0.00730972 | 0.375486
2972677 | 지상 5층 | 지상 5층 | 2971239 | 705.972 | 0.186493 | 0.00705972 | 0.372986
2972678 | 지상 5층 | 지상 5층 | 2971239 | 705.972 | 0.186493 | 0.00705972 | 0.372986
2972679 | 지상 5층 | 지상 5층 | 2971239 | 300 | 0.085 | 0.003 | 0.16
2972680 | 지상 5층 | 지상 5층 | 2971239 | 600 | 0.16 | 0.006 | 0.3
2972681 | 지상 5층 | 지상 5층 | 2971239 | 1100 | 0.285 | 0.011 | 0.56
2972781 | 지상 5층 | 지상 5층 | 2971239 | 730.972 | 0.192743 | 0.00730972 | 0.375486
2972782 | 지상 5층 | 지상 5층 | 2971239 | 730.972 | 0.192743 | 0.00730972 | 0.375486
2972783 | 지상 5층 | 지상 5층 | 2971239 | 705.972 | 0.186493 | 0.00705972 | 0.372986
2972784 | 지상 5층 | 지상 5층 | 2971239 | 705.972 | 0.186493 | 0.00705972 | 0.372986
2972785 | 지상 5층 | 지상 5층 | 2971239 | 300 | 0.085 | 0.003 | 0.16
2972786 | 지상 5층 | 지상 5층 | 2971239 | 600 | 0.16 | 0.006 | 0.3
2972787 | 지상 5층 | 지상 5층 | 2971239 | 1100 | 0.285 | 0.011 | 0.56
2972895 | 지상 5층 | 지상 5층 | 2971239 | 730.972 | 0.192743 | 0.00730972 | 0.375486
2972896 | 지상 5층 | 지상 5층 | 2971239 | 730.972 | 0.192743 | 0.00730972 | 0.375486
2972897 | 지상 5층 | 지상 5층 | 2971239 | 705.972 | 0.186493 | 0.00705972 | 0.372986
2972898 | 지상 5층 | 지상 5층 | 2971239 | 705.972 | 0.186493 | 0.00705972 | 0.372986
2972899 | 지상 5층 | 지상 5층 | 2971239 | 300 | 0.085 | 0.003 | 0.16
2972900 | 지상 5층 | 지상 5층 | 2971239 | 600 | 0.16 | 0.006 | 0.3
2972901 | 지상 5층 | 지상 5층 | 2971239 | 1100 | 0.285 | 0.011 | 0.56
2973007 | 지상 5층 | 지상 5층 | 2971239 | 1000 | 0.26 | 0.01 | 0.52
2973008 | 지상 5층 | 지상 5층 | 2971239 | 730.972 | 0.192743 | 0.00730972 | 0.375486
2973009 | 지상 5층 | 지상 5층 | 2971239 | 705.972 | 0.186493 | 0.00705972 | 0.372986
2973010 | 지상 5층 | 지상 5층 | 2971239 | 705.972 | 0.186493 | 0.00705972 | 0.372986
2973011 | 지상 5층 | 지상 5층 | 2971239 | 300 | 0.085 | 0.003 | 0.16
2973012 | 지상 5층 | 지상 5층 | 2971239 | 600 | 0.16 | 0.006 | 0.3
2973013 | 지상 5층 | 지상 5층 | 2971239 | 1100 | 0.285 | 0.011 | 0.56
2973084 | 지상 5층 | 지상 5층 | 2971239 | 756 | 0.199 | 0.00756 | 0.388
2973085 | 지상 5층 | 지상 5층 | 2971239 | 1000 | 0.26 | 0.01 | 0.52
2973086 | 지상 5층 | 지상 5층 | 2971239 | 1000 | 0.26 | 0.01 | 0.52
2973087 | 지상 5층 | 지상 5층 | 2971239 | 1000 | 0.26 | 0.01 | 0.52
2973088 | 지상 5층 | 지상 5층 | 2971239 | 300 | 0.085 | 0.003 | 0.16
2973089 | 지상 5층 | 지상 5층 | 2971239 | 600 | 0.16 | 0.006 | 0.3
2973090 | 지상 5층 | 지상 5층 | 2971239 | 1100 | 0.285 | 0.011 | 0.56
2973232 | 지상 5층 | 지상 5층 | 2971239 | 756 | 0.199 | 0.00756 | 0.388
2973233 | 지상 5층 | 지상 5층 | 2971239 | 756 | 0.199 | 0.00756 | 0.388
2973234 | 지상 5층 | 지상 5층 | 2971239 | 731 | 0.19275 | 0.00731 | 0.3855
2973235 | 지상 5층 | 지상 5층 | 2971239 | 731 | 0.19275 | 0.00731 | 0.3855
2973236 | 지상 5층 | 지상 5층 | 2971239 | 300 | 0.085 | 0.003 | 0.16
2973237 | 지상 5층 | 지상 5층 | 2971239 | 600 | 0.16 | 0.006 | 0.3
2973238 | 지상 5층 | 지상 5층 | 2971239 | 1100 | 0.285 | 0.011 | 0.56
2973334 | 지상 5층 | 지상 5층 | 2971239 | 756 | 0.199 | 0.00756 | 0.388
2973335 | 지상 5층 | 지상 5층 | 2971239 | 756 | 0.199 | 0.00756 | 0.388
2973336 | 지상 5층 | 지상 5층 | 2971239 | 731 | 0.19275 | 0.00731 | 0.3855
2973337 | 지상 5층 | 지상 5층 | 2971239 | 731 | 0.19275 | 0.00731 | 0.3855
2973338 | 지상 5층 | 지상 5층 | 2971239 | 300 | 0.085 | 0.003 | 0.16
2973339 | 지상 5층 | 지상 5층 | 2971239 | 600 | 0.16 | 0.006 | 0.3
2973340 | 지상 5층 | 지상 5층 | 2971239 | 1100 | 0.285 | 0.011 | 0.56
2973450 | 지상 5층 | 지상 5층 | 2971239 | 756 | 0.199 | 0.00756 | 0.388
2973451 | 지상 5층 | 지상 5층 | 2971239 | 756 | 0.199 | 0.00756 | 0.388
2973452 | 지상 5층 | 지상 5층 | 2971239 | 731 | 0.19275 | 0.00731 | 0.3855
2973453 | 지상 5층 | 지상 5층 | 2971239 | 731 | 0.19275 | 0.00731 | 0.3855
2973454 | 지상 5층 | 지상 5층 | 2971239 | 300 | 0.085 | 0.003 | 0.16
2973455 | 지상 5층 | 지상 5층 | 2971239 | 600 | 0.16 | 0.006 | 0.3
2973456 | 지상 5층 | 지상 5층 | 2971239 | 1100 | 0.285 | 0.011 | 0.56
2973530 | 지상 5층 | 지상 5층 | 2971239 | 1000 | 0.26 | 0.01 | 0.52
2973531 | 지상 5층 | 지상 5층 | 2971239 | 756 | 0.199 | 0.00756 | 0.388
2973532 | 지상 5층 | 지상 5층 | 2971239 | 731 | 0.19275 | 0.00731 | 0.3855
2973533 | 지상 5층 | 지상 5층 | 2971239 | 731 | 0.19275 | 0.00731 | 0.3855
2973534 | 지상 5층 | 지상 5층 | 2971239 | 300 | 0.085 | 0.003 | 0.16
2973535 | 지상 5층 | 지상 5층 | 2971239 | 600 | 0.16 | 0.006 | 0.3
2973536 | 지상 5층 | 지상 5층 | 2971239 | 1100 | 0.285 | 0.011 | 0.56
2973578 | 지상 5층 | 지상 5층 | 2971239 | 756.839 | 0.19921 | 0.00756839 | 0.38842
2973579 | 지상 5층 | 지상 5층 | 2971239 | 1000 | 0.26 | 0.01 | 0.52
2973580 | 지상 5층 | 지상 5층 | 2971239 | 1000 | 0.26 | 0.01 | 0.52
2973581 | 지상 5층 | 지상 5층 | 2971239 | 1000 | 0.26 | 0.01 | 0.52
2973582 | 지상 5층 | 지상 5층 | 2971239 | 300 | 0.085 | 0.003 | 0.16
2973583 | 지상 5층 | 지상 5층 | 2971239 | 600 | 0.16 | 0.006 | 0.3
2973584 | 지상 5층 | 지상 5층 | 2971239 | 1100 | 0.285 | 0.011 | 0.56
2973702 | 지상 5층 | 지상 5층 | 2971239 | 756.839 | 0.19921 | 0.00756839 | 0.38842
2973703 | 지상 5층 | 지상 5층 | 2971239 | 756.839 | 0.19921 | 0.00756839 | 0.38842
2973704 | 지상 5층 | 지상 5층 | 2971239 | 731.839 | 0.19296 | 0.00731839 | 0.38592
2973705 | 지상 5층 | 지상 5층 | 2971239 | 731.839 | 0.19296 | 0.00731839 | 0.38592
2973706 | 지상 5층 | 지상 5층 | 2971239 | 300 | 0.085 | 0.003 | 0.16
2973707 | 지상 5층 | 지상 5층 | 2971239 | 600 | 0.16 | 0.006 | 0.3
2973708 | 지상 5층 | 지상 5층 | 2971239 | 1100 | 0.285 | 0.011 | 0.56
2973752 | 지상 5층 | 지상 5층 | 2971239 | 756.839 | 0.19921 | 0.00756839 | 0.38842
2973753 | 지상 5층 | 지상 5층 | 2971239 | 756.839 | 0.19921 | 0.00756839 | 0.38842
2973754 | 지상 5층 | 지상 5층 | 2971239 | 731.839 | 0.19296 | 0.00731839 | 0.38592
2973755 | 지상 5층 | 지상 5층 | 2971239 | 731.839 | 0.19296 | 0.00731839 | 0.38592
2973756 | 지상 5층 | 지상 5층 | 2971239 | 300 | 0.085 | 0.003 | 0.16
2973757 | 지상 5층 | 지상 5층 | 2971239 | 600 | 0.16 | 0.006 | 0.3
2973758 | 지상 5층 | 지상 5층 | 2971239 | 1100 | 0.285 | 0.011 | 0.56
2973826 | 지상 5층 | 지상 5층 | 2971239 | 756.839 | 0.19921 | 0.00756839 | 0.38842
2973827 | 지상 5층 | 지상 5층 | 2971239 | 756.839 | 0.19921 | 0.00756839 | 0.38842
2973828 | 지상 5층 | 지상 5층 | 2971239 | 731.839 | 0.19296 | 0.00731839 | 0.38592
2973829 | 지상 5층 | 지상 5층 | 2971239 | 731.839 | 0.19296 | 0.00731839 | 0.38592
2973830 | 지상 5층 | 지상 5층 | 2971239 | 300 | 0.085 | 0.003 | 0.16
2973831 | 지상 5층 | 지상 5층 | 2971239 | 600 | 0.16 | 0.006 | 0.3
2973832 | 지상 5층 | 지상 5층 | 2971239 | 1100 | 0.285 | 0.011 | 0.56
2973918 | 지상 5층 | 지상 5층 | 2971239 | 756.839 | 0.19921 | 0.00756839 | 0.38842
2973919 | 지상 5층 | 지상 5층 | 2971239 | 756.839 | 0.19921 | 0.00756839 | 0.38842
2973920 | 지상 5층 | 지상 5층 | 2971239 | 731.839 | 0.19296 | 0.00731839 | 0.38592
2973921 | 지상 5층 | 지상 5층 | 2971239 | 731.839 | 0.19296 | 0.00731839 | 0.38592
2973922 | 지상 5층 | 지상 5층 | 2971239 | 300 | 0.085 | 0.003 | 0.16
2973923 | 지상 5층 | 지상 5층 | 2971239 | 600 | 0.16 | 0.006 | 0.3
2973924 | 지상 5층 | 지상 5층 | 2971239 | 1100 | 0.285 | 0.011 | 0.56
2974234 | 지상 5층 | 지상 5층 | 2971239 | 730.972 | 0.192743 | 0.00730972 | 0.375486
2974235 | 지상 5층 | 지상 5층 | 2971239 | 730.972 | 0.192743 | 0.00730972 | 0.375486
2974236 | 지상 5층 | 지상 5층 | 2971239 | 705.972 | 0.186493 | 0.00705972 | 0.372986
2974237 | 지상 5층 | 지상 5층 | 2971239 | 705.972 | 0.186493 | 0.00705972 | 0.372986
2974239 | 지상 5층 | 지상 5층 | 2971239 | 650 | 0.1725 | 0.0065 | 0.345
2974346 | 지상 5층 | 지상 5층 | 2971239 | 730.972 | 0.192743 | 0.00730972 | 0.375486
2974347 | 지상 5층 | 지상 5층 | 2971239 | 730.972 | 0.192743 | 0.00730972 | 0.375486
2974348 | 지상 5층 | 지상 5층 | 2971239 | 705.972 | 0.186493 | 0.00705972 | 0.372986
2974349 | 지상 5층 | 지상 5층 | 2971239 | 705.972 | 0.186493 | 0.00705972 | 0.372986
2974350 | 지상 5층 | 지상 5층 | 2971239 | 650 | 0.1725 | 0.0065 | 0.345
2974383 | 지상 5층 | 지상 5층 | 2971239 | 730.972 | 0.192743 | 0.00730972 | 0.375486
2974384 | 지상 5층 | 지상 5층 | 2971239 | 730.972 | 0.192743 | 0.00730972 | 0.375486
2974385 | 지상 5층 | 지상 5층 | 2971239 | 705.972 | 0.186493 | 0.00705972 | 0.372986
2974386 | 지상 5층 | 지상 5층 | 2971239 | 705.972 | 0.186493 | 0.00705972 | 0.372986
2974387 | 지상 5층 | 지상 5층 | 2971239 | 650 | 0.1725 | 0.0065 | 0.345
2974420 | 지상 5층 | 지상 5층 | 2971239 | 730.972 | 0.192743 | 0.00730972 | 0.375486
2974421 | 지상 5층 | 지상 5층 | 2971239 | 730.972 | 0.192743 | 0.00730972 | 0.375486
2974422 | 지상 5층 | 지상 5층 | 2971239 | 705.972 | 0.186493 | 0.00705972 | 0.372986
2974423 | 지상 5층 | 지상 5층 | 2971239 | 705.972 | 0.186493 | 0.00705972 | 0.372986
2974424 | 지상 5층 | 지상 5층 | 2971239 | 650 | 0.1725 | 0.0065 | 0.345
2974457 | 지상 5층 | 지상 5층 | 2971239 | 730.972 | 0.192743 | 0.00730972 | 0.375486
2974458 | 지상 5층 | 지상 5층 | 2971239 | 730.972 | 0.192743 | 0.00730972 | 0.375486
2974459 | 지상 5층 | 지상 5층 | 2971239 | 705.972 | 0.186493 | 0.00705972 | 0.372986
2974460 | 지상 5층 | 지상 5층 | 2971239 | 705.972 | 0.186493 | 0.00705972 | 0.372986
2974461 | 지상 5층 | 지상 5층 | 2971239 | 650 | 0.1725 | 0.0065 | 0.345
2974494 | 지상 5층 | 지상 5층 | 2971239 | 730.972 | 0.192743 | 0.00730972 | 0.375486
2974495 | 지상 5층 | 지상 5층 | 2971239 | 730.972 | 0.192743 | 0.00730972 | 0.375486
2974496 | 지상 5층 | 지상 5층 | 2971239 | 705.972 | 0.186493 | 0.00705972 | 0.372986
2974497 | 지상 5층 | 지상 5층 | 2971239 | 705.972 | 0.186493 | 0.00705972 | 0.372986
2974498 | 지상 5층 | 지상 5층 | 2971239 | 650 | 0.1725 | 0.0065 | 0.345
2974531 | 지상 5층 | 지상 5층 | 2971239 | 730.972 | 0.192743 | 0.00730972 | 0.375486
2974532 | 지상 5층 | 지상 5층 | 2971239 | 730.972 | 0.192743 | 0.00730972 | 0.375486
2974533 | 지상 5층 | 지상 5층 | 2971239 | 705.972 | 0.186493 | 0.00705972 | 0.372986
2974534 | 지상 5층 | 지상 5층 | 2971239 | 705.972 | 0.186493 | 0.00705972 | 0.372986
2974535 | 지상 5층 | 지상 5층 | 2971239 | 650 | 0.1725 | 0.0065 | 0.345
2974568 | 지상 5층 | 지상 5층 | 2971239 | 756 | 0.199 | 0.00756 | 0.388
2974569 | 지상 5층 | 지상 5층 | 2971239 | 756 | 0.199 | 0.00756 | 0.388
2974570 | 지상 5층 | 지상 5층 | 2971239 | 731 | 0.19275 | 0.00731 | 0.3855
2974571 | 지상 5층 | 지상 5층 | 2971239 | 731 | 0.19275 | 0.00731 | 0.3855
2974572 | 지상 5층 | 지상 5층 | 2971239 | 650 | 0.1725 | 0.0065 | 0.345
2974602 | 지상 5층 | 지상 5층 | 2971239 | 756 | 0.199 | 0.00756 | 0.388
2974603 | 지상 5층 | 지상 5층 | 2971239 | 756 | 0.199 | 0.00756 | 0.388
2974604 | 지상 5층 | 지상 5층 | 2971239 | 731 | 0.19275 | 0.00731 | 0.3855
2974605 | 지상 5층 | 지상 5층 | 2971239 | 731 | 0.19275 | 0.00731 | 0.3855
2974606 | 지상 5층 | 지상 5층 | 2971239 | 650 | 0.1725 | 0.0065 | 0.345
2974639 | 지상 5층 | 지상 5층 | 2971239 | 756 | 0.199 | 0.00756 | 0.388
2974640 | 지상 5층 | 지상 5층 | 2971239 | 756 | 0.199 | 0.00756 | 0.388
2974641 | 지상 5층 | 지상 5층 | 2971239 | 731 | 0.19275 | 0.00731 | 0.3855
2974642 | 지상 5층 | 지상 5층 | 2971239 | 731 | 0.19275 | 0.00731 | 0.3855
2974643 | 지상 5층 | 지상 5층 | 2971239 | 650 | 0.1725 | 0.0065 | 0.345
2974676 | 지상 5층 | 지상 5층 | 2971239 | 756 | 0.199 | 0.00756 | 0.388
2974677 | 지상 5층 | 지상 5층 | 2971239 | 756 | 0.199 | 0.00756 | 0.388
2974678 | 지상 5층 | 지상 5층 | 2971239 | 731 | 0.19275 | 0.00731 | 0.3855
2974679 | 지상 5층 | 지상 5층 | 2971239 | 731 | 0.19275 | 0.00731 | 0.3855
2974680 | 지상 5층 | 지상 5층 | 2971239 | 650 | 0.1725 | 0.0065 | 0.345
2974709 | 지상 5층 | 지상 5층 | 2971239 | 756.839 | 0.19921 | 0.00756839 | 0.38842
2974710 | 지상 5층 | 지상 5층 | 2971239 | 756.839 | 0.19921 | 0.00756839 | 0.38842
2974711 | 지상 5층 | 지상 5층 | 2971239 | 731.839 | 0.19296 | 0.00731839 | 0.38592
2974712 | 지상 5층 | 지상 5층 | 2971239 | 731.839 | 0.19296 | 0.00731839 | 0.38592
2974713 | 지상 5층 | 지상 5층 | 2971239 | 650 | 0.1725 | 0.0065 | 0.345
2974746 | 지상 5층 | 지상 5층 | 2971239 | 756.839 | 0.19921 | 0.00756839 | 0.38842
2974747 | 지상 5층 | 지상 5층 | 2971239 | 756.839 | 0.19921 | 0.00756839 | 0.38842
2974748 | 지상 5층 | 지상 5층 | 2971239 | 731.839 | 0.19296 | 0.00731839 | 0.38592
2974749 | 지상 5층 | 지상 5층 | 2971239 | 731.839 | 0.19296 | 0.00731839 | 0.38592
2974750 | 지상 5층 | 지상 5층 | 2971239 | 650 | 0.1725 | 0.0065 | 0.345
2974783 | 지상 5층 | 지상 5층 | 2971239 | 756.839 | 0.19921 | 0.00756839 | 0.38842
2974784 | 지상 5층 | 지상 5층 | 2971239 | 756.839 | 0.19921 | 0.00756839 | 0.38842
2974785 | 지상 5층 | 지상 5층 | 2971239 | 731.839 | 0.19296 | 0.00731839 | 0.38592
2974786 | 지상 5층 | 지상 5층 | 2971239 | 731.839 | 0.19296 | 0.00731839 | 0.38592
2974787 | 지상 5층 | 지상 5층 | 2971239 | 650 | 0.1725 | 0.0065 | 0.345
2974820 | 지상 5층 | 지상 5층 | 2971239 | 756.839 | 0.19921 | 0.00756839 | 0.38842
2974821 | 지상 5층 | 지상 5층 | 2971239 | 756.839 | 0.19921 | 0.00756839 | 0.38842
2974822 | 지상 5층 | 지상 5층 | 2971239 | 731.839 | 0.19296 | 0.00731839 | 0.38592
2974823 | 지상 5층 | 지상 5층 | 2971239 | 731.839 | 0.19296 | 0.00731839 | 0.38592
2974824 | 지상 5층 | 지상 5층 | 2971239 | 650 | 0.1725 | 0.0065 | 0.345
2974846 | 지상 5층 | 지상 5층 | 2971239 | 756.839 | 0.19921 | 0.00756839 | 0.38842
2974847 | 지상 5층 | 지상 5층 | 2971239 | 731.839 | 0.19296 | 0.00731839 | 0.38592
2974848 | 지상 5층 | 지상 5층 | 2971239 | 731.839 | 0.19296 | 0.00731839 | 0.38592
2974849 | 지상 5층 | 지상 5층 | 2971239 | 913.84 | 0.23846 | 0.0091384 | 0.46692
2974850 | 지상 5층 | 지상 5층 | 2971239 | 650 | 0.1725 | 0.0065 | 0.345
2975044 | 지상 6층 | 지상 6층 | 2975042 | 912.605 | 0.238151 | 0.00912605 | 0.476303
2975045 | 지상 6층 | 지상 6층 | 2975042 | 908.395 | 0.237099 | 0.00908395 | 0.464197
2975047 | 지상 6층 | 지상 6층 | 2975042 | 1100 | 0.285 | 0.011 | 0.56
2975051 | 지상 6층 | 지상 6층 | 2975042 | 300 | 0.085 | 0.003 | 0.16
2975052 | 지상 6층 | 지상 6층 | 2975042 | 883.395 | 0.230849 | 0.00883395 | 0.461697
2975056 | 지상 6층 | 지상 6층 | 2975042 | 600 | 0.16 | 0.006 | 0.3
2975057 | 지상 6층 | 지상 6층 | 2975042 | 883.395 | 0.230849 | 0.00883395 | 0.461697
2975062 | 지상 6층 | 지상 6층 | 2975042 | 727 | 0.19175 | 0.00727 | 0.3735
2975063 | 지상 6층 | 지상 6층 | 2975042 | 912.605 | 0.238151 | 0.00912605 | 0.476303
2975064 | 지상 6층 | 지상 6층 | 2975042 | 912.605 | 0.238151 | 0.00912605 | 0.476303
2975065 | 지상 6층 | 지상 6층 | 2975042 | 912.605 | 0.238151 | 0.00912605 | 0.476303
2975066 | 지상 6층 | 지상 6층 | 2975042 | 300 | 0.085 | 0.003 | 0.16
2975067 | 지상 6층 | 지상 6층 | 2975042 | 600 | 0.16 | 0.006 | 0.3
2975068 | 지상 6층 | 지상 6층 | 2975042 | 1100 | 0.285 | 0.011 | 0.56
2975073 | 지상 6층 | 지상 6층 | 2975042 | 741 | 0.19525 | 0.00741 | 0.3805
2975074 | 지상 6층 | 지상 6층 | 2975042 | 667 | 0.17675 | 0.00667 | 0.3435
2975075 | 지상 6층 | 지상 6층 | 2975042 | 642 | 0.1705 | 0.00642 | 0.341
2975076 | 지상 6층 | 지상 6층 | 2975042 | 642 | 0.1705 | 0.00642 | 0.341
2975077 | 지상 6층 | 지상 6층 | 2975042 | 300 | 0.085 | 0.003 | 0.16
2975078 | 지상 6층 | 지상 6층 | 2975042 | 600 | 0.16 | 0.006 | 0.3
2975079 | 지상 6층 | 지상 6층 | 2975042 | 1100 | 0.285 | 0.011 | 0.56
2975084 | 지상 6층 | 지상 6층 | 2975042 | 741 | 0.19525 | 0.00741 | 0.3805
2975085 | 지상 6층 | 지상 6층 | 2975042 | 741 | 0.19525 | 0.00741 | 0.3805
2975086 | 지상 6층 | 지상 6층 | 2975042 | 716 | 0.189 | 0.00716 | 0.378
2975087 | 지상 6층 | 지상 6층 | 2975042 | 716 | 0.189 | 0.00716 | 0.378
2975088 | 지상 6층 | 지상 6층 | 2975042 | 300 | 0.085 | 0.003 | 0.16
2975089 | 지상 6층 | 지상 6층 | 2975042 | 600 | 0.16 | 0.006 | 0.3
2975090 | 지상 6층 | 지상 6층 | 2975042 | 1100 | 0.285 | 0.011 | 0.56
2975095 | 지상 6층 | 지상 6층 | 2975042 | 741 | 0.19525 | 0.00741 | 0.3805
2975096 | 지상 6층 | 지상 6층 | 2975042 | 741 | 0.19525 | 0.00741 | 0.3805
2975097 | 지상 6층 | 지상 6층 | 2975042 | 716 | 0.189 | 0.00716 | 0.378
2975098 | 지상 6층 | 지상 6층 | 2975042 | 716 | 0.189 | 0.00716 | 0.378
2975099 | 지상 6층 | 지상 6층 | 2975042 | 300 | 0.085 | 0.003 | 0.16
2975100 | 지상 6층 | 지상 6층 | 2975042 | 600 | 0.16 | 0.006 | 0.3
2975101 | 지상 6층 | 지상 6층 | 2975042 | 1100 | 0.285 | 0.011 | 0.56
2975106 | 지상 6층 | 지상 6층 | 2975042 | 741 | 0.19525 | 0.00741 | 0.3805
2975107 | 지상 6층 | 지상 6층 | 2975042 | 741 | 0.19525 | 0.00741 | 0.3805
2975108 | 지상 6층 | 지상 6층 | 2975042 | 716 | 0.189 | 0.00716 | 0.378
2975109 | 지상 6층 | 지상 6층 | 2975042 | 716 | 0.189 | 0.00716 | 0.378
2975110 | 지상 6층 | 지상 6층 | 2975042 | 300 | 0.085 | 0.003 | 0.16
2975111 | 지상 6층 | 지상 6층 | 2975042 | 600 | 0.16 | 0.006 | 0.3
2975112 | 지상 6층 | 지상 6층 | 2975042 | 1100 | 0.285 | 0.011 | 0.56
2975117 | 지상 6층 | 지상 6층 | 2975042 | 741 | 0.19525 | 0.00741 | 0.3805
2975118 | 지상 6층 | 지상 6층 | 2975042 | 741 | 0.19525 | 0.00741 | 0.3805
2975119 | 지상 6층 | 지상 6층 | 2975042 | 716 | 0.189 | 0.00716 | 0.378
2975120 | 지상 6층 | 지상 6층 | 2975042 | 716 | 0.189 | 0.00716 | 0.378
2975121 | 지상 6층 | 지상 6층 | 2975042 | 300 | 0.085 | 0.003 | 0.16
2975122 | 지상 6층 | 지상 6층 | 2975042 | 600 | 0.16 | 0.006 | 0.3
2975123 | 지상 6층 | 지상 6층 | 2975042 | 1100 | 0.285 | 0.011 | 0.56
2975128 | 지상 6층 | 지상 6층 | 2975042 | 741 | 0.19525 | 0.00741 | 0.3805
2975129 | 지상 6층 | 지상 6층 | 2975042 | 741 | 0.19525 | 0.00741 | 0.3805
2975130 | 지상 6층 | 지상 6층 | 2975042 | 716 | 0.189 | 0.00716 | 0.378
2975131 | 지상 6층 | 지상 6층 | 2975042 | 716 | 0.189 | 0.00716 | 0.378
2975132 | 지상 6층 | 지상 6층 | 2975042 | 300 | 0.085 | 0.003 | 0.16
2975133 | 지상 6층 | 지상 6층 | 2975042 | 600 | 0.16 | 0.006 | 0.3
2975134 | 지상 6층 | 지상 6층 | 2975042 | 1100 | 0.285 | 0.011 | 0.56
2975139 | 지상 6층 | 지상 6층 | 2975042 | 1000 | 0.26 | 0.01 | 0.52
2975140 | 지상 6층 | 지상 6층 | 2975042 | 801 | 0.21025 | 0.00801 | 0.4105
2975141 | 지상 6층 | 지상 6층 | 2975042 | 776 | 0.204 | 0.00776 | 0.408
2975142 | 지상 6층 | 지상 6층 | 2975042 | 776 | 0.204 | 0.00776 | 0.408
2975143 | 지상 6층 | 지상 6층 | 2975042 | 300 | 0.085 | 0.003 | 0.16
2975144 | 지상 6층 | 지상 6층 | 2975042 | 600 | 0.16 | 0.006 | 0.3
2975145 | 지상 6층 | 지상 6층 | 2975042 | 1100 | 0.285 | 0.011 | 0.56
2975150 | 지상 6층 | 지상 6층 | 2975042 | 801 | 0.21025 | 0.00801 | 0.4105
2975151 | 지상 6층 | 지상 6층 | 2975042 | 1000 | 0.26 | 0.01 | 0.52
2975152 | 지상 6층 | 지상 6층 | 2975042 | 1000 | 0.26 | 0.01 | 0.52
2975153 | 지상 6층 | 지상 6층 | 2975042 | 1000 | 0.26 | 0.01 | 0.52
2975154 | 지상 6층 | 지상 6층 | 2975042 | 300 | 0.085 | 0.003 | 0.16
2975155 | 지상 6층 | 지상 6층 | 2975042 | 600 | 0.16 | 0.006 | 0.3
2975156 | 지상 6층 | 지상 6층 | 2975042 | 1100 | 0.285 | 0.011 | 0.56
2975161 | 지상 6층 | 지상 6층 | 2975042 | 741 | 0.19525 | 0.00741 | 0.3805
2975162 | 지상 6층 | 지상 6층 | 2975042 | 741 | 0.19525 | 0.00741 | 0.3805
2975163 | 지상 6층 | 지상 6층 | 2975042 | 716 | 0.189 | 0.00716 | 0.378
2975164 | 지상 6층 | 지상 6층 | 2975042 | 716 | 0.189 | 0.00716 | 0.378
2975165 | 지상 6층 | 지상 6층 | 2975042 | 300 | 0.085 | 0.003 | 0.16
2975166 | 지상 6층 | 지상 6층 | 2975042 | 600 | 0.16 | 0.006 | 0.3
2975167 | 지상 6층 | 지상 6층 | 2975042 | 1100 | 0.285 | 0.011 | 0.56
2975172 | 지상 6층 | 지상 6층 | 2975042 | 741 | 0.19525 | 0.00741 | 0.3805
2975173 | 지상 6층 | 지상 6층 | 2975042 | 741 | 0.19525 | 0.00741 | 0.3805
2975174 | 지상 6층 | 지상 6층 | 2975042 | 716 | 0.189 | 0.00716 | 0.378
2975175 | 지상 6층 | 지상 6층 | 2975042 | 716 | 0.189 | 0.00716 | 0.378
2975176 | 지상 6층 | 지상 6층 | 2975042 | 300 | 0.085 | 0.003 | 0.16
2975177 | 지상 6층 | 지상 6층 | 2975042 | 600 | 0.16 | 0.006 | 0.3
2975178 | 지상 6층 | 지상 6층 | 2975042 | 1100 | 0.285 | 0.011 | 0.56
2975183 | 지상 6층 | 지상 6층 | 2975042 | 741 | 0.19525 | 0.00741 | 0.3805
2975184 | 지상 6층 | 지상 6층 | 2975042 | 741 | 0.19525 | 0.00741 | 0.3805
2975185 | 지상 6층 | 지상 6층 | 2975042 | 716 | 0.189 | 0.00716 | 0.378
2975186 | 지상 6층 | 지상 6층 | 2975042 | 716 | 0.189 | 0.00716 | 0.378
2975187 | 지상 6층 | 지상 6층 | 2975042 | 300 | 0.085 | 0.003 | 0.16
2975188 | 지상 6층 | 지상 6층 | 2975042 | 600 | 0.16 | 0.006 | 0.3
2975189 | 지상 6층 | 지상 6층 | 2975042 | 1100 | 0.285 | 0.011 | 0.56
2975194 | 지상 6층 | 지상 6층 | 2975042 | 1000 | 0.26 | 0.01 | 0.52
2975195 | 지상 6층 | 지상 6층 | 2975042 | 801 | 0.21025 | 0.00801 | 0.4105
2975196 | 지상 6층 | 지상 6층 | 2975042 | 776 | 0.204 | 0.00776 | 0.408
2975197 | 지상 6층 | 지상 6층 | 2975042 | 776 | 0.204 | 0.00776 | 0.408
2975198 | 지상 6층 | 지상 6층 | 2975042 | 300 | 0.085 | 0.003 | 0.16
2975199 | 지상 6층 | 지상 6층 | 2975042 | 600 | 0.16 | 0.006 | 0.3
2975200 | 지상 6층 | 지상 6층 | 2975042 | 1100 | 0.285 | 0.011 | 0.56
2975205 | 지상 6층 | 지상 6층 | 2975042 | 814 | 0.2135 | 0.00814 | 0.417
2975206 | 지상 6층 | 지상 6층 | 2975042 | 1000 | 0.26 | 0.01 | 0.52
2975207 | 지상 6층 | 지상 6층 | 2975042 | 1000 | 0.26 | 0.01 | 0.52
2975208 | 지상 6층 | 지상 6층 | 2975042 | 1000 | 0.26 | 0.01 | 0.52
2975209 | 지상 6층 | 지상 6층 | 2975042 | 300 | 0.085 | 0.003 | 0.16
2975210 | 지상 6층 | 지상 6층 | 2975042 | 600 | 0.16 | 0.006 | 0.3
2975211 | 지상 6층 | 지상 6층 | 2975042 | 1100 | 0.285 | 0.011 | 0.56
2975216 | 지상 6층 | 지상 6층 | 2975042 | 754 | 0.1985 | 0.00754 | 0.387
2975217 | 지상 6층 | 지상 6층 | 2975042 | 754 | 0.1985 | 0.00754 | 0.387
2975218 | 지상 6층 | 지상 6층 | 2975042 | 729 | 0.19225 | 0.00729 | 0.3845
2975219 | 지상 6층 | 지상 6층 | 2975042 | 729 | 0.19225 | 0.00729 | 0.3845
2975220 | 지상 6층 | 지상 6층 | 2975042 | 300 | 0.085 | 0.003 | 0.16
2975221 | 지상 6층 | 지상 6층 | 2975042 | 600 | 0.16 | 0.006 | 0.3
2975222 | 지상 6층 | 지상 6층 | 2975042 | 1100 | 0.285 | 0.011 | 0.56
2975227 | 지상 6층 | 지상 6층 | 2975042 | 754 | 0.1985 | 0.00754 | 0.387
2975228 | 지상 6층 | 지상 6층 | 2975042 | 754 | 0.1985 | 0.00754 | 0.387
2975229 | 지상 6층 | 지상 6층 | 2975042 | 729 | 0.19225 | 0.00729 | 0.3845
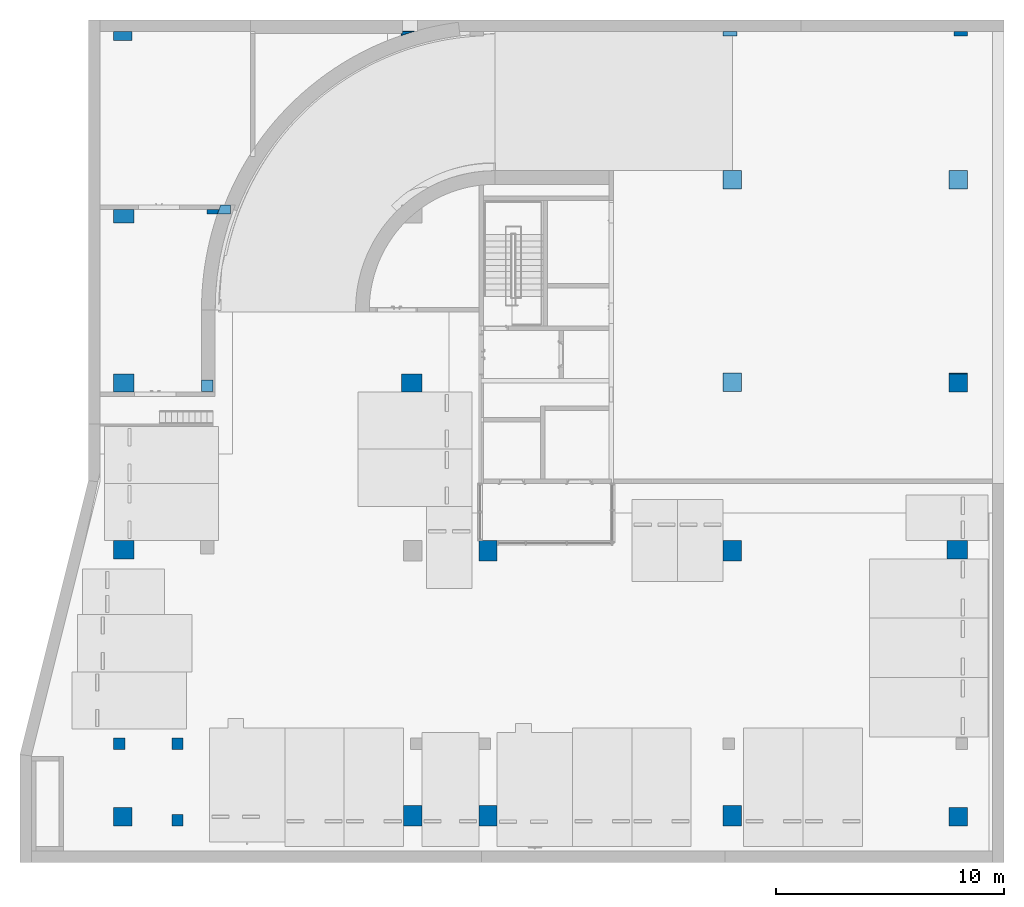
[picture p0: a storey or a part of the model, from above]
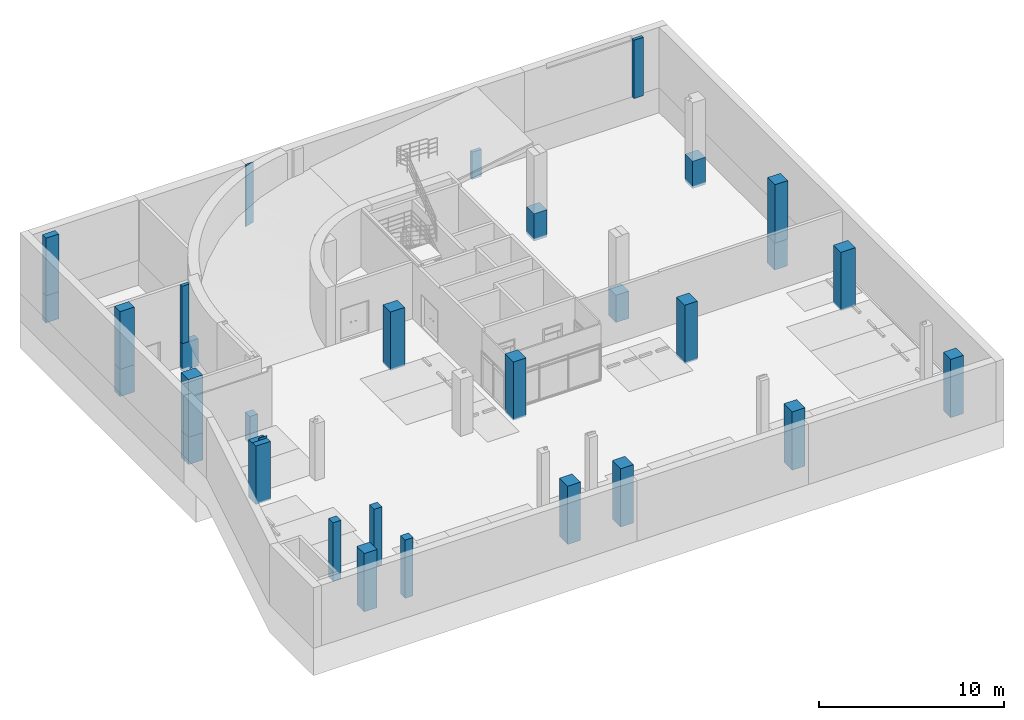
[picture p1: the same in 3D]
Properties of the parts of a building model (IFC2X3), part 19 of 39

# IfcMember: 직사각형 멀리언:CW200-직사각형 멀리언 50x200mm (8700)
Name (직사각형 멀리언:CW200-직사각형 멀리언 50x200mm:...) | In | 레벨 | 호스트 ID | 길이 (mm) = Span (mm) | 면적 (m2) = CrossSectionArea (m2) | 체적 (m3) = NetVolume (m3) | NetSurfaceArea (m2)
2975230 | 지상 6층 | 지상 6층 | 2975042 | 729 | 0.19225 | 0.00729 | 0.3845
2975231 | 지상 6층 | 지상 6층 | 2975042 | 300 | 0.085 | 0.003 | 0.16
2975232 | 지상 6층 | 지상 6층 | 2975042 | 600 | 0.16 | 0.006 | 0.3
2975233 | 지상 6층 | 지상 6층 | 2975042 | 1100 | 0.285 | 0.011 | 0.56
2975238 | 지상 6층 | 지상 6층 | 2975042 | 754 | 0.1985 | 0.00754 | 0.387
2975239 | 지상 6층 | 지상 6층 | 2975042 | 754 | 0.1985 | 0.00754 | 0.387
2975240 | 지상 6층 | 지상 6층 | 2975042 | 729 | 0.19225 | 0.00729 | 0.3845
2975241 | 지상 6층 | 지상 6층 | 2975042 | 729 | 0.19225 | 0.00729 | 0.3845
2975242 | 지상 6층 | 지상 6층 | 2975042 | 300 | 0.085 | 0.003 | 0.16
2975243 | 지상 6층 | 지상 6층 | 2975042 | 600 | 0.16 | 0.006 | 0.3
2975244 | 지상 6층 | 지상 6층 | 2975042 | 1100 | 0.285 | 0.011 | 0.56
2975249 | 지상 6층 | 지상 6층 | 2975042 | 725 | 0.19125 | 0.00725 | 0.3725
2975250 | 지상 6층 | 지상 6층 | 2975042 | 754 | 0.1985 | 0.00754 | 0.387
2975251 | 지상 6층 | 지상 6층 | 2975042 | 729 | 0.19225 | 0.00729 | 0.3845
2975252 | 지상 6층 | 지상 6층 | 2975042 | 729 | 0.19225 | 0.00729 | 0.3845
2975253 | 지상 6층 | 지상 6층 | 2975042 | 300 | 0.085 | 0.003 | 0.16
2975254 | 지상 6층 | 지상 6층 | 2975042 | 600 | 0.16 | 0.006 | 0.3
2975255 | 지상 6층 | 지상 6층 | 2975042 | 1100 | 0.285 | 0.011 | 0.56
2975260 | 지상 6층 | 지상 6층 | 2975042 | 667 | 0.17675 | 0.00667 | 0.3435
2975261 | 지상 6층 | 지상 6층 | 2975042 | 727 | 0.19175 | 0.00727 | 0.3735
2975262 | 지상 6층 | 지상 6층 | 2975042 | 702 | 0.1855 | 0.00702 | 0.371
2975263 | 지상 6층 | 지상 6층 | 2975042 | 702 | 0.1855 | 0.00702 | 0.371
2975264 | 지상 6층 | 지상 6층 | 2975042 | 650 | 0.1725 | 0.0065 | 0.345
2975269 | 지상 6층 | 지상 6층 | 2975042 | 741 | 0.19525 | 0.00741 | 0.3805
2975270 | 지상 6층 | 지상 6층 | 2975042 | 741 | 0.19525 | 0.00741 | 0.3805
2975271 | 지상 6층 | 지상 6층 | 2975042 | 716 | 0.189 | 0.00716 | 0.378
2975272 | 지상 6층 | 지상 6층 | 2975042 | 716 | 0.189 | 0.00716 | 0.378
2975273 | 지상 6층 | 지상 6층 | 2975042 | 650 | 0.1725 | 0.0065 | 0.345
2975278 | 지상 6층 | 지상 6층 | 2975042 | 741 | 0.19525 | 0.00741 | 0.3805
2975279 | 지상 6층 | 지상 6층 | 2975042 | 741 | 0.19525 | 0.00741 | 0.3805
2975280 | 지상 6층 | 지상 6층 | 2975042 | 716 | 0.189 | 0.00716 | 0.378
2975281 | 지상 6층 | 지상 6층 | 2975042 | 716 | 0.189 | 0.00716 | 0.378
2975282 | 지상 6층 | 지상 6층 | 2975042 | 650 | 0.1725 | 0.0065 | 0.345
2975287 | 지상 6층 | 지상 6층 | 2975042 | 741 | 0.19525 | 0.00741 | 0.3805
2975288 | 지상 6층 | 지상 6층 | 2975042 | 741 | 0.19525 | 0.00741 | 0.3805
2975289 | 지상 6층 | 지상 6층 | 2975042 | 716 | 0.189 | 0.00716 | 0.378
2975290 | 지상 6층 | 지상 6층 | 2975042 | 716 | 0.189 | 0.00716 | 0.378
2975291 | 지상 6층 | 지상 6층 | 2975042 | 650 | 0.1725 | 0.0065 | 0.345
2975296 | 지상 6층 | 지상 6층 | 2975042 | 741 | 0.19525 | 0.00741 | 0.3805
2975297 | 지상 6층 | 지상 6층 | 2975042 | 741 | 0.19525 | 0.00741 | 0.3805
2975298 | 지상 6층 | 지상 6층 | 2975042 | 716 | 0.189 | 0.00716 | 0.378
2975299 | 지상 6층 | 지상 6층 | 2975042 | 716 | 0.189 | 0.00716 | 0.378
2975300 | 지상 6층 | 지상 6층 | 2975042 | 650 | 0.1725 | 0.0065 | 0.345
2975305 | 지상 6층 | 지상 6층 | 2975042 | 741 | 0.19525 | 0.00741 | 0.3805
2975306 | 지상 6층 | 지상 6층 | 2975042 | 741 | 0.19525 | 0.00741 | 0.3805
2975307 | 지상 6층 | 지상 6층 | 2975042 | 716 | 0.189 | 0.00716 | 0.378
2975308 | 지상 6층 | 지상 6층 | 2975042 | 716 | 0.189 | 0.00716 | 0.378
2975309 | 지상 6층 | 지상 6층 | 2975042 | 650 | 0.1725 | 0.0065 | 0.345
2975314 | 지상 6층 | 지상 6층 | 2975042 | 801 | 0.21025 | 0.00801 | 0.4105
2975315 | 지상 6층 | 지상 6층 | 2975042 | 741 | 0.19525 | 0.00741 | 0.3805
2975316 | 지상 6층 | 지상 6층 | 2975042 | 716 | 0.189 | 0.00716 | 0.378
2975317 | 지상 6층 | 지상 6층 | 2975042 | 716 | 0.189 | 0.00716 | 0.378
2975318 | 지상 6층 | 지상 6층 | 2975042 | 650 | 0.1725 | 0.0065 | 0.345
2975323 | 지상 6층 | 지상 6층 | 2975042 | 741 | 0.19525 | 0.00741 | 0.3805
2975324 | 지상 6층 | 지상 6층 | 2975042 | 801 | 0.21025 | 0.00801 | 0.4105
2975325 | 지상 6층 | 지상 6층 | 2975042 | 776 | 0.204 | 0.00776 | 0.408
2975326 | 지상 6층 | 지상 6층 | 2975042 | 776 | 0.204 | 0.00776 | 0.408
2975327 | 지상 6층 | 지상 6층 | 2975042 | 650 | 0.1725 | 0.0065 | 0.345
2975332 | 지상 6층 | 지상 6층 | 2975042 | 741 | 0.19525 | 0.00741 | 0.3805
2975333 | 지상 6층 | 지상 6층 | 2975042 | 741 | 0.19525 | 0.00741 | 0.3805
2975334 | 지상 6층 | 지상 6층 | 2975042 | 716 | 0.189 | 0.00716 | 0.378
2975335 | 지상 6층 | 지상 6층 | 2975042 | 716 | 0.189 | 0.00716 | 0.378
2975336 | 지상 6층 | 지상 6층 | 2975042 | 650 | 0.1725 | 0.0065 | 0.345
2975341 | 지상 6층 | 지상 6층 | 2975042 | 741 | 0.19525 | 0.00741 | 0.3805
2975342 | 지상 6층 | 지상 6층 | 2975042 | 741 | 0.19525 | 0.00741 | 0.3805
2975343 | 지상 6층 | 지상 6층 | 2975042 | 716 | 0.189 | 0.00716 | 0.378
2975344 | 지상 6층 | 지상 6층 | 2975042 | 716 | 0.189 | 0.00716 | 0.378
2975345 | 지상 6층 | 지상 6층 | 2975042 | 650 | 0.1725 | 0.0065 | 0.345
2975350 | 지상 6층 | 지상 6층 | 2975042 | 801 | 0.21025 | 0.00801 | 0.4105
2975351 | 지상 6층 | 지상 6층 | 2975042 | 741 | 0.19525 | 0.00741 | 0.3805
2975352 | 지상 6층 | 지상 6층 | 2975042 | 716 | 0.189 | 0.00716 | 0.378
2975353 | 지상 6층 | 지상 6층 | 2975042 | 716 | 0.189 | 0.00716 | 0.378
2975354 | 지상 6층 | 지상 6층 | 2975042 | 650 | 0.1725 | 0.0065 | 0.345
2975359 | 지상 6층 | 지상 6층 | 2975042 | 754 | 0.1985 | 0.00754 | 0.387
2975360 | 지상 6층 | 지상 6층 | 2975042 | 814 | 0.2135 | 0.00814 | 0.417
2975361 | 지상 6층 | 지상 6층 | 2975042 | 789 | 0.20725 | 0.00789 | 0.4145
2975362 | 지상 6층 | 지상 6층 | 2975042 | 789 | 0.20725 | 0.00789 | 0.4145
2975363 | 지상 6층 | 지상 6층 | 2975042 | 650 | 0.1725 | 0.0065 | 0.345
2975368 | 지상 6층 | 지상 6층 | 2975042 | 754 | 0.1985 | 0.00754 | 0.387
2975369 | 지상 6층 | 지상 6층 | 2975042 | 754 | 0.1985 | 0.00754 | 0.387
2975370 | 지상 6층 | 지상 6층 | 2975042 | 729 | 0.19225 | 0.00729 | 0.3845
2975371 | 지상 6층 | 지상 6층 | 2975042 | 729 | 0.19225 | 0.00729 | 0.3845
2975372 | 지상 6층 | 지상 6층 | 2975042 | 650 | 0.1725 | 0.0065 | 0.345
2975377 | 지상 6층 | 지상 6층 | 2975042 | 754 | 0.1985 | 0.00754 | 0.387
2975378 | 지상 6층 | 지상 6층 | 2975042 | 754 | 0.1985 | 0.00754 | 0.387
2975379 | 지상 6층 | 지상 6층 | 2975042 | 729 | 0.19225 | 0.00729 | 0.3845
2975380 | 지상 6층 | 지상 6층 | 2975042 | 729 | 0.19225 | 0.00729 | 0.3845
2975381 | 지상 6층 | 지상 6층 | 2975042 | 650 | 0.1725 | 0.0065 | 0.345
2975386 | 지상 6층 | 지상 6층 | 2975042 | 754 | 0.1985 | 0.00754 | 0.387
2975387 | 지상 6층 | 지상 6층 | 2975042 | 754 | 0.1985 | 0.00754 | 0.387
2975388 | 지상 6층 | 지상 6층 | 2975042 | 729 | 0.19225 | 0.00729 | 0.3845
2975389 | 지상 6층 | 지상 6층 | 2975042 | 729 | 0.19225 | 0.00729 | 0.3845
2975390 | 지상 6층 | 지상 6층 | 2975042 | 650 | 0.1725 | 0.0065 | 0.345
2975395 | 지상 6층 | 지상 6층 | 2975042 | 725 | 0.19125 | 0.00725 | 0.3725
2975396 | 지상 6층 | 지상 6층 | 2975042 | 700 | 0.185 | 0.007 | 0.37
2975397 | 지상 6층 | 지상 6층 | 2975042 | 700 | 0.185 | 0.007 | 0.37
2975398 | 지상 6층 | 지상 6층 | 2975042 | 908.395 | 0.237099 | 0.00908395 | 0.464197
2975399 | 지상 6층 | 지상 6층 | 2975042 | 650 | 0.1725 | 0.0065 | 0.345
2975404 | 지상 7층 | 지상 7층 | 2975402 | 912.605 | 0.238151 | 0.00912605 | 0.476303
2975405 | 지상 7층 | 지상 7층 | 2975402 | 726.395 | 0.191599 | 0.00726395 | 0.373197
2975407 | 지상 7층 | 지상 7층 | 2975402 | 1100 | 0.285 | 0.011 | 0.56
2975411 | 지상 7층 | 지상 7층 | 2975402 | 300 | 0.085 | 0.003 | 0.16
2975412 | 지상 7층 | 지상 7층 | 2975402 | 701.395 | 0.185349 | 0.00701395 | 0.370697
2975416 | 지상 7층 | 지상 7층 | 2975402 | 600 | 0.16 | 0.006 | 0.3
2975417 | 지상 7층 | 지상 7층 | 2975402 | 701.395 | 0.185349 | 0.00701395 | 0.370697
2975422 | 지상 7층 | 지상 7층 | 2975402 | 727 | 0.19175 | 0.00727 | 0.3735
2975423 | 지상 7층 | 지상 7층 | 2975402 | 912.605 | 0.238151 | 0.00912605 | 0.476303
2975424 | 지상 7층 | 지상 7층 | 2975402 | 912.605 | 0.238151 | 0.00912605 | 0.476303
2975425 | 지상 7층 | 지상 7층 | 2975402 | 912.605 | 0.238151 | 0.00912605 | 0.476303
2975426 | 지상 7층 | 지상 7층 | 2975402 | 300 | 0.085 | 0.003 | 0.16
2975427 | 지상 7층 | 지상 7층 | 2975402 | 600 | 0.16 | 0.006 | 0.3
2975428 | 지상 7층 | 지상 7층 | 2975402 | 1100 | 0.285 | 0.011 | 0.56
2975433 | 지상 7층 | 지상 7층 | 2975402 | 741 | 0.19525 | 0.00741 | 0.3805
2975434 | 지상 7층 | 지상 7층 | 2975402 | 667 | 0.17675 | 0.00667 | 0.3435
2975435 | 지상 7층 | 지상 7층 | 2975402 | 642 | 0.1705 | 0.00642 | 0.341
2975436 | 지상 7층 | 지상 7층 | 2975402 | 642 | 0.1705 | 0.00642 | 0.341
2975437 | 지상 7층 | 지상 7층 | 2975402 | 300 | 0.085 | 0.003 | 0.16
2975438 | 지상 7층 | 지상 7층 | 2975402 | 600 | 0.16 | 0.006 | 0.3
2975439 | 지상 7층 | 지상 7층 | 2975402 | 1100 | 0.285 | 0.011 | 0.56
2975444 | 지상 7층 | 지상 7층 | 2975402 | 741 | 0.19525 | 0.00741 | 0.3805
2975445 | 지상 7층 | 지상 7층 | 2975402 | 741 | 0.19525 | 0.00741 | 0.3805
2975446 | 지상 7층 | 지상 7층 | 2975402 | 716 | 0.189 | 0.00716 | 0.378
2975447 | 지상 7층 | 지상 7층 | 2975402 | 716 | 0.189 | 0.00716 | 0.378
2975448 | 지상 7층 | 지상 7층 | 2975402 | 300 | 0.085 | 0.003 | 0.16
2975449 | 지상 7층 | 지상 7층 | 2975402 | 600 | 0.16 | 0.006 | 0.3
2975450 | 지상 7층 | 지상 7층 | 2975402 | 1100 | 0.285 | 0.011 | 0.56
2975455 | 지상 7층 | 지상 7층 | 2975402 | 741 | 0.19525 | 0.00741 | 0.3805
2975456 | 지상 7층 | 지상 7층 | 2975402 | 741 | 0.19525 | 0.00741 | 0.3805
2975457 | 지상 7층 | 지상 7층 | 2975402 | 716 | 0.189 | 0.00716 | 0.378
2975458 | 지상 7층 | 지상 7층 | 2975402 | 716 | 0.189 | 0.00716 | 0.378
2975459 | 지상 7층 | 지상 7층 | 2975402 | 300 | 0.085 | 0.003 | 0.16
2975460 | 지상 7층 | 지상 7층 | 2975402 | 600 | 0.16 | 0.006 | 0.3
2975461 | 지상 7층 | 지상 7층 | 2975402 | 1100 | 0.285 | 0.011 | 0.56
2975466 | 지상 7층 | 지상 7층 | 2975402 | 741 | 0.19525 | 0.00741 | 0.3805
2975467 | 지상 7층 | 지상 7층 | 2975402 | 741 | 0.19525 | 0.00741 | 0.3805
2975468 | 지상 7층 | 지상 7층 | 2975402 | 716 | 0.189 | 0.00716 | 0.378
2975469 | 지상 7층 | 지상 7층 | 2975402 | 716 | 0.189 | 0.00716 | 0.378
2975470 | 지상 7층 | 지상 7층 | 2975402 | 300 | 0.085 | 0.003 | 0.16
2975471 | 지상 7층 | 지상 7층 | 2975402 | 600 | 0.16 | 0.006 | 0.3
2975472 | 지상 7층 | 지상 7층 | 2975402 | 1100 | 0.285 | 0.011 | 0.56
2975477 | 지상 7층 | 지상 7층 | 2975402 | 741 | 0.19525 | 0.00741 | 0.3805
2975478 | 지상 7층 | 지상 7층 | 2975402 | 741 | 0.19525 | 0.00741 | 0.3805
2975479 | 지상 7층 | 지상 7층 | 2975402 | 716 | 0.189 | 0.00716 | 0.378
2975480 | 지상 7층 | 지상 7층 | 2975402 | 716 | 0.189 | 0.00716 | 0.378
2975481 | 지상 7층 | 지상 7층 | 2975402 | 300 | 0.085 | 0.003 | 0.16
2975482 | 지상 7층 | 지상 7층 | 2975402 | 600 | 0.16 | 0.006 | 0.3
2975483 | 지상 7층 | 지상 7층 | 2975402 | 1100 | 0.285 | 0.011 | 0.56
2975488 | 지상 7층 | 지상 7층 | 2975402 | 741 | 0.19525 | 0.00741 | 0.3805
2975489 | 지상 7층 | 지상 7층 | 2975402 | 741 | 0.19525 | 0.00741 | 0.3805
2975490 | 지상 7층 | 지상 7층 | 2975402 | 716 | 0.189 | 0.00716 | 0.378
2975491 | 지상 7층 | 지상 7층 | 2975402 | 716 | 0.189 | 0.00716 | 0.378
2975492 | 지상 7층 | 지상 7층 | 2975402 | 300 | 0.085 | 0.003 | 0.16
2975493 | 지상 7층 | 지상 7층 | 2975402 | 600 | 0.16 | 0.006 | 0.3
2975494 | 지상 7층 | 지상 7층 | 2975402 | 1100 | 0.285 | 0.011 | 0.56
2975499 | 지상 7층 | 지상 7층 | 2975402 | 1000 | 0.26 | 0.01 | 0.52
2975500 | 지상 7층 | 지상 7층 | 2975402 | 801 | 0.21025 | 0.00801 | 0.4105
2975501 | 지상 7층 | 지상 7층 | 2975402 | 776 | 0.204 | 0.00776 | 0.408
2975502 | 지상 7층 | 지상 7층 | 2975402 | 776 | 0.204 | 0.00776 | 0.408
2975503 | 지상 7층 | 지상 7층 | 2975402 | 300 | 0.085 | 0.003 | 0.16
2975504 | 지상 7층 | 지상 7층 | 2975402 | 600 | 0.16 | 0.006 | 0.3
2975505 | 지상 7층 | 지상 7층 | 2975402 | 1100 | 0.285 | 0.011 | 0.56
2975510 | 지상 7층 | 지상 7층 | 2975402 | 801 | 0.21025 | 0.00801 | 0.4105
2975511 | 지상 7층 | 지상 7층 | 2975402 | 1000 | 0.26 | 0.01 | 0.52
2975512 | 지상 7층 | 지상 7층 | 2975402 | 1000 | 0.26 | 0.01 | 0.52
2975513 | 지상 7층 | 지상 7층 | 2975402 | 1000 | 0.26 | 0.01 | 0.52
2975514 | 지상 7층 | 지상 7층 | 2975402 | 300 | 0.085 | 0.003 | 0.16
2975515 | 지상 7층 | 지상 7층 | 2975402 | 600 | 0.16 | 0.006 | 0.3
2975516 | 지상 7층 | 지상 7층 | 2975402 | 1100 | 0.285 | 0.011 | 0.56
2975521 | 지상 7층 | 지상 7층 | 2975402 | 741 | 0.19525 | 0.00741 | 0.3805
2975522 | 지상 7층 | 지상 7층 | 2975402 | 741 | 0.19525 | 0.00741 | 0.3805
2975523 | 지상 7층 | 지상 7층 | 2975402 | 716 | 0.189 | 0.00716 | 0.378
2975524 | 지상 7층 | 지상 7층 | 2975402 | 716 | 0.189 | 0.00716 | 0.378
2975525 | 지상 7층 | 지상 7층 | 2975402 | 300 | 0.085 | 0.003 | 0.16
2975526 | 지상 7층 | 지상 7층 | 2975402 | 600 | 0.16 | 0.006 | 0.3
2975527 | 지상 7층 | 지상 7층 | 2975402 | 1100 | 0.285 | 0.011 | 0.56
2975532 | 지상 7층 | 지상 7층 | 2975402 | 741 | 0.19525 | 0.00741 | 0.3805
2975533 | 지상 7층 | 지상 7층 | 2975402 | 741 | 0.19525 | 0.00741 | 0.3805
2975534 | 지상 7층 | 지상 7층 | 2975402 | 716 | 0.189 | 0.00716 | 0.378
2975535 | 지상 7층 | 지상 7층 | 2975402 | 716 | 0.189 | 0.00716 | 0.378
2975536 | 지상 7층 | 지상 7층 | 2975402 | 300 | 0.085 | 0.003 | 0.16
2975537 | 지상 7층 | 지상 7층 | 2975402 | 600 | 0.16 | 0.006 | 0.3
2975538 | 지상 7층 | 지상 7층 | 2975402 | 1100 | 0.285 | 0.011 | 0.56
2975543 | 지상 7층 | 지상 7층 | 2975402 | 741 | 0.19525 | 0.00741 | 0.3805
2975544 | 지상 7층 | 지상 7층 | 2975402 | 741 | 0.19525 | 0.00741 | 0.3805
2975545 | 지상 7층 | 지상 7층 | 2975402 | 716 | 0.189 | 0.00716 | 0.378
2975546 | 지상 7층 | 지상 7층 | 2975402 | 716 | 0.189 | 0.00716 | 0.378
2975547 | 지상 7층 | 지상 7층 | 2975402 | 300 | 0.085 | 0.003 | 0.16
2975548 | 지상 7층 | 지상 7층 | 2975402 | 600 | 0.16 | 0.006 | 0.3
2975549 | 지상 7층 | 지상 7층 | 2975402 | 1100 | 0.285 | 0.011 | 0.56
2975554 | 지상 7층 | 지상 7층 | 2975402 | 1000 | 0.26 | 0.01 | 0.52
2975555 | 지상 7층 | 지상 7층 | 2975402 | 801 | 0.21025 | 0.00801 | 0.4105
2975556 | 지상 7층 | 지상 7층 | 2975402 | 776 | 0.204 | 0.00776 | 0.408
2975557 | 지상 7층 | 지상 7층 | 2975402 | 776 | 0.204 | 0.00776 | 0.408
2975558 | 지상 7층 | 지상 7층 | 2975402 | 300 | 0.085 | 0.003 | 0.16
2975559 | 지상 7층 | 지상 7층 | 2975402 | 600 | 0.16 | 0.006 | 0.3
2975560 | 지상 7층 | 지상 7층 | 2975402 | 1100 | 0.285 | 0.011 | 0.56
2975565 | 지상 7층 | 지상 7층 | 2975402 | 814 | 0.2135 | 0.00814 | 0.417
2975566 | 지상 7층 | 지상 7층 | 2975402 | 1000 | 0.26 | 0.01 | 0.52
2975567 | 지상 7층 | 지상 7층 | 2975402 | 1000 | 0.26 | 0.01 | 0.52
2975568 | 지상 7층 | 지상 7층 | 2975402 | 1000 | 0.26 | 0.01 | 0.52
2975569 | 지상 7층 | 지상 7층 | 2975402 | 300 | 0.085 | 0.003 | 0.16
2975570 | 지상 7층 | 지상 7층 | 2975402 | 600 | 0.16 | 0.006 | 0.3
2975571 | 지상 7층 | 지상 7층 | 2975402 | 1100 | 0.285 | 0.011 | 0.56
2975576 | 지상 7층 | 지상 7층 | 2975402 | 754 | 0.1985 | 0.00754 | 0.387
2975577 | 지상 7층 | 지상 7층 | 2975402 | 754 | 0.1985 | 0.00754 | 0.387
2975578 | 지상 7층 | 지상 7층 | 2975402 | 729 | 0.19225 | 0.00729 | 0.3845
2975579 | 지상 7층 | 지상 7층 | 2975402 | 729 | 0.19225 | 0.00729 | 0.3845
2975580 | 지상 7층 | 지상 7층 | 2975402 | 300 | 0.085 | 0.003 | 0.16
2975581 | 지상 7층 | 지상 7층 | 2975402 | 600 | 0.16 | 0.006 | 0.3
2975582 | 지상 7층 | 지상 7층 | 2975402 | 1100 | 0.285 | 0.011 | 0.56
2975587 | 지상 7층 | 지상 7층 | 2975402 | 754 | 0.1985 | 0.00754 | 0.387
2975588 | 지상 7층 | 지상 7층 | 2975402 | 754 | 0.1985 | 0.00754 | 0.387
2975589 | 지상 7층 | 지상 7층 | 2975402 | 729 | 0.19225 | 0.00729 | 0.3845
2975590 | 지상 7층 | 지상 7층 | 2975402 | 729 | 0.19225 | 0.00729 | 0.3845
2975591 | 지상 7층 | 지상 7층 | 2975402 | 300 | 0.085 | 0.003 | 0.16
2975592 | 지상 7층 | 지상 7층 | 2975402 | 600 | 0.16 | 0.006 | 0.3
2975593 | 지상 7층 | 지상 7층 | 2975402 | 1100 | 0.285 | 0.011 | 0.56
2975598 | 지상 7층 | 지상 7층 | 2975402 | 754 | 0.1985 | 0.00754 | 0.387
2975599 | 지상 7층 | 지상 7층 | 2975402 | 754 | 0.1985 | 0.00754 | 0.387
2975600 | 지상 7층 | 지상 7층 | 2975402 | 729 | 0.19225 | 0.00729 | 0.3845
2975601 | 지상 7층 | 지상 7층 | 2975402 | 729 | 0.19225 | 0.00729 | 0.3845
2975602 | 지상 7층 | 지상 7층 | 2975402 | 300 | 0.085 | 0.003 | 0.16
2975603 | 지상 7층 | 지상 7층 | 2975402 | 600 | 0.16 | 0.006 | 0.3
2975604 | 지상 7층 | 지상 7층 | 2975402 | 1100 | 0.285 | 0.011 | 0.56
2975609 | 지상 7층 | 지상 7층 | 2975402 | 725 | 0.19125 | 0.00725 | 0.3725
2975610 | 지상 7층 | 지상 7층 | 2975402 | 754 | 0.1985 | 0.00754 | 0.387
2975611 | 지상 7층 | 지상 7층 | 2975402 | 729 | 0.19225 | 0.00729 | 0.3845
2975612 | 지상 7층 | 지상 7층 | 2975402 | 729 | 0.19225 | 0.00729 | 0.3845
2975613 | 지상 7층 | 지상 7층 | 2975402 | 300 | 0.085 | 0.003 | 0.16
2975614 | 지상 7층 | 지상 7층 | 2975402 | 600 | 0.16 | 0.006 | 0.3
2975615 | 지상 7층 | 지상 7층 | 2975402 | 1100 | 0.285 | 0.011 | 0.56
2975620 | 지상 7층 | 지상 7층 | 2975402 | 667 | 0.17675 | 0.00667 | 0.3435
2975621 | 지상 7층 | 지상 7층 | 2975402 | 727 | 0.19175 | 0.00727 | 0.3735
2975622 | 지상 7층 | 지상 7층 | 2975402 | 702 | 0.1855 | 0.00702 | 0.371
2975623 | 지상 7층 | 지상 7층 | 2975402 | 702 | 0.1855 | 0.00702 | 0.371
2975624 | 지상 7층 | 지상 7층 | 2975402 | 650 | 0.1725 | 0.0065 | 0.345
2975629 | 지상 7층 | 지상 7층 | 2975402 | 741 | 0.19525 | 0.00741 | 0.3805
2975630 | 지상 7층 | 지상 7층 | 2975402 | 741 | 0.19525 | 0.00741 | 0.3805
2975631 | 지상 7층 | 지상 7층 | 2975402 | 716 | 0.189 | 0.00716 | 0.378
2975632 | 지상 7층 | 지상 7층 | 2975402 | 716 | 0.189 | 0.00716 | 0.378
2975633 | 지상 7층 | 지상 7층 | 2975402 | 650 | 0.1725 | 0.0065 | 0.345
2975638 | 지상 7층 | 지상 7층 | 2975402 | 741 | 0.19525 | 0.00741 | 0.3805
2975639 | 지상 7층 | 지상 7층 | 2975402 | 741 | 0.19525 | 0.00741 | 0.3805
2975640 | 지상 7층 | 지상 7층 | 2975402 | 716 | 0.189 | 0.00716 | 0.378
2975641 | 지상 7층 | 지상 7층 | 2975402 | 716 | 0.189 | 0.00716 | 0.378
2975642 | 지상 7층 | 지상 7층 | 2975402 | 650 | 0.1725 | 0.0065 | 0.345
2975647 | 지상 7층 | 지상 7층 | 2975402 | 741 | 0.19525 | 0.00741 | 0.3805
2975648 | 지상 7층 | 지상 7층 | 2975402 | 741 | 0.19525 | 0.00741 | 0.3805
2975649 | 지상 7층 | 지상 7층 | 2975402 | 716 | 0.189 | 0.00716 | 0.378
2975650 | 지상 7층 | 지상 7층 | 2975402 | 716 | 0.189 | 0.00716 | 0.378
2975651 | 지상 7층 | 지상 7층 | 2975402 | 650 | 0.1725 | 0.0065 | 0.345
2975656 | 지상 7층 | 지상 7층 | 2975402 | 741 | 0.19525 | 0.00741 | 0.3805
2975657 | 지상 7층 | 지상 7층 | 2975402 | 741 | 0.19525 | 0.00741 | 0.3805
2975658 | 지상 7층 | 지상 7층 | 2975402 | 716 | 0.189 | 0.00716 | 0.378
2975659 | 지상 7층 | 지상 7층 | 2975402 | 716 | 0.189 | 0.00716 | 0.378
2975660 | 지상 7층 | 지상 7층 | 2975402 | 650 | 0.1725 | 0.0065 | 0.345
2975665 | 지상 7층 | 지상 7층 | 2975402 | 741 | 0.19525 | 0.00741 | 0.3805
2975666 | 지상 7층 | 지상 7층 | 2975402 | 741 | 0.19525 | 0.00741 | 0.3805
2975667 | 지상 7층 | 지상 7층 | 2975402 | 716 | 0.189 | 0.00716 | 0.378
2975668 | 지상 7층 | 지상 7층 | 2975402 | 716 | 0.189 | 0.00716 | 0.378
2975669 | 지상 7층 | 지상 7층 | 2975402 | 650 | 0.1725 | 0.0065 | 0.345
2975674 | 지상 7층 | 지상 7층 | 2975402 | 801 | 0.21025 | 0.00801 | 0.4105
2975675 | 지상 7층 | 지상 7층 | 2975402 | 741 | 0.19525 | 0.00741 | 0.3805
2975676 | 지상 7층 | 지상 7층 | 2975402 | 716 | 0.189 | 0.00716 | 0.378
2975677 | 지상 7층 | 지상 7층 | 2975402 | 716 | 0.189 | 0.00716 | 0.378
2975678 | 지상 7층 | 지상 7층 | 2975402 | 650 | 0.1725 | 0.0065 | 0.345
2975683 | 지상 7층 | 지상 7층 | 2975402 | 741 | 0.19525 | 0.00741 | 0.3805
2975684 | 지상 7층 | 지상 7층 | 2975402 | 801 | 0.21025 | 0.00801 | 0.4105
2975685 | 지상 7층 | 지상 7층 | 2975402 | 776 | 0.204 | 0.00776 | 0.408
2975686 | 지상 7층 | 지상 7층 | 2975402 | 776 | 0.204 | 0.00776 | 0.408
2975687 | 지상 7층 | 지상 7층 | 2975402 | 650 | 0.1725 | 0.0065 | 0.345
2975692 | 지상 7층 | 지상 7층 | 2975402 | 741 | 0.19525 | 0.00741 | 0.3805
2975693 | 지상 7층 | 지상 7층 | 2975402 | 741 | 0.19525 | 0.00741 | 0.3805
2975694 | 지상 7층 | 지상 7층 | 2975402 | 716 | 0.189 | 0.00716 | 0.378
2975695 | 지상 7층 | 지상 7층 | 2975402 | 716 | 0.189 | 0.00716 | 0.378
2975696 | 지상 7층 | 지상 7층 | 2975402 | 650 | 0.1725 | 0.0065 | 0.345
2975701 | 지상 7층 | 지상 7층 | 2975402 | 741 | 0.19525 | 0.00741 | 0.3805
2975702 | 지상 7층 | 지상 7층 | 2975402 | 741 | 0.19525 | 0.00741 | 0.3805
2975703 | 지상 7층 | 지상 7층 | 2975402 | 716 | 0.189 | 0.00716 | 0.378
2975704 | 지상 7층 | 지상 7층 | 2975402 | 716 | 0.189 | 0.00716 | 0.378
2975705 | 지상 7층 | 지상 7층 | 2975402 | 650 | 0.1725 | 0.0065 | 0.345
2975710 | 지상 7층 | 지상 7층 | 2975402 | 801 | 0.21025 | 0.00801 | 0.4105
2975711 | 지상 7층 | 지상 7층 | 2975402 | 741 | 0.19525 | 0.00741 | 0.3805
2975712 | 지상 7층 | 지상 7층 | 2975402 | 716 | 0.189 | 0.00716 | 0.378
2975713 | 지상 7층 | 지상 7층 | 2975402 | 716 | 0.189 | 0.00716 | 0.378
2975714 | 지상 7층 | 지상 7층 | 2975402 | 650 | 0.1725 | 0.0065 | 0.345
2975719 | 지상 7층 | 지상 7층 | 2975402 | 754 | 0.1985 | 0.00754 | 0.387
2975720 | 지상 7층 | 지상 7층 | 2975402 | 814 | 0.2135 | 0.00814 | 0.417
2975721 | 지상 7층 | 지상 7층 | 2975402 | 789 | 0.20725 | 0.00789 | 0.4145
2975722 | 지상 7층 | 지상 7층 | 2975402 | 789 | 0.20725 | 0.00789 | 0.4145
2975723 | 지상 7층 | 지상 7층 | 2975402 | 650 | 0.1725 | 0.0065 | 0.345
2975728 | 지상 7층 | 지상 7층 | 2975402 | 754 | 0.1985 | 0.00754 | 0.387
2975729 | 지상 7층 | 지상 7층 | 2975402 | 754 | 0.1985 | 0.00754 | 0.387
2975730 | 지상 7층 | 지상 7층 | 2975402 | 729 | 0.19225 | 0.00729 | 0.3845
2975731 | 지상 7층 | 지상 7층 | 2975402 | 729 | 0.19225 | 0.00729 | 0.3845
2975732 | 지상 7층 | 지상 7층 | 2975402 | 650 | 0.1725 | 0.0065 | 0.345
2975737 | 지상 7층 | 지상 7층 | 2975402 | 754 | 0.1985 | 0.00754 | 0.387
2975738 | 지상 7층 | 지상 7층 | 2975402 | 754 | 0.1985 | 0.00754 | 0.387
2975739 | 지상 7층 | 지상 7층 | 2975402 | 729 | 0.19225 | 0.00729 | 0.3845
2975740 | 지상 7층 | 지상 7층 | 2975402 | 729 | 0.19225 | 0.00729 | 0.3845
2975741 | 지상 7층 | 지상 7층 | 2975402 | 650 | 0.1725 | 0.0065 | 0.345
2975746 | 지상 7층 | 지상 7층 | 2975402 | 754 | 0.1985 | 0.00754 | 0.387
2975747 | 지상 7층 | 지상 7층 | 2975402 | 754 | 0.1985 | 0.00754 | 0.387
2975748 | 지상 7층 | 지상 7층 | 2975402 | 729 | 0.19225 | 0.00729 | 0.3845
2975749 | 지상 7층 | 지상 7층 | 2975402 | 729 | 0.19225 | 0.00729 | 0.3845
2975750 | 지상 7층 | 지상 7층 | 2975402 | 650 | 0.1725 | 0.0065 | 0.345
2975755 | 지상 7층 | 지상 7층 | 2975402 | 725 | 0.19125 | 0.00725 | 0.3725
2975756 | 지상 7층 | 지상 7층 | 2975402 | 700 | 0.185 | 0.007 | 0.37
2975757 | 지상 7층 | 지상 7층 | 2975402 | 700 | 0.185 | 0.007 | 0.37
2975758 | 지상 7층 | 지상 7층 | 2975402 | 726.395 | 0.191599 | 0.00726395 | 0.373197
2975759 | 지상 7층 | 지상 7층 | 2975402 | 650 | 0.1725 | 0.0065 | 0.345
2975764 | 지상 8층 | 지상 8층 | 2975762 | 912.605 | 0.238151 | 0.00912605 | 0.476303
2975765 | 지상 8층 | 지상 8층 | 2975762 | 908.395 | 0.237099 | 0.00908395 | 0.464197
2975767 | 지상 8층 | 지상 8층 | 2975762 | 1100 | 0.285 | 0.011 | 0.56
2975771 | 지상 8층 | 지상 8층 | 2975762 | 300 | 0.085 | 0.003 | 0.16
2975772 | 지상 8층 | 지상 8층 | 2975762 | 883.395 | 0.230849 | 0.00883395 | 0.461697
2975776 | 지상 8층 | 지상 8층 | 2975762 | 600 | 0.16 | 0.006 | 0.3
2975777 | 지상 8층 | 지상 8층 | 2975762 | 883.395 | 0.230849 | 0.00883395 | 0.461697
2975782 | 지상 8층 | 지상 8층 | 2975762 | 727 | 0.19175 | 0.00727 | 0.3735
2975783 | 지상 8층 | 지상 8층 | 2975762 | 912.605 | 0.238151 | 0.00912605 | 0.476303
2975784 | 지상 8층 | 지상 8층 | 2975762 | 912.605 | 0.238151 | 0.00912605 | 0.476303
2975785 | 지상 8층 | 지상 8층 | 2975762 | 912.605 | 0.238151 | 0.00912605 | 0.476303
2975786 | 지상 8층 | 지상 8층 | 2975762 | 300 | 0.085 | 0.003 | 0.16
2975787 | 지상 8층 | 지상 8층 | 2975762 | 600 | 0.16 | 0.006 | 0.3
2975788 | 지상 8층 | 지상 8층 | 2975762 | 1100 | 0.285 | 0.011 | 0.56
2975793 | 지상 8층 | 지상 8층 | 2975762 | 741 | 0.19525 | 0.00741 | 0.3805
2975794 | 지상 8층 | 지상 8층 | 2975762 | 667 | 0.17675 | 0.00667 | 0.3435
2975795 | 지상 8층 | 지상 8층 | 2975762 | 642 | 0.1705 | 0.00642 | 0.341
2975796 | 지상 8층 | 지상 8층 | 2975762 | 642 | 0.1705 | 0.00642 | 0.341
2975797 | 지상 8층 | 지상 8층 | 2975762 | 300 | 0.085 | 0.003 | 0.16
2975798 | 지상 8층 | 지상 8층 | 2975762 | 600 | 0.16 | 0.006 | 0.3
2975799 | 지상 8층 | 지상 8층 | 2975762 | 1100 | 0.285 | 0.011 | 0.56
2975804 | 지상 8층 | 지상 8층 | 2975762 | 741 | 0.19525 | 0.00741 | 0.3805
2975805 | 지상 8층 | 지상 8층 | 2975762 | 741 | 0.19525 | 0.00741 | 0.3805
2975806 | 지상 8층 | 지상 8층 | 2975762 | 716 | 0.189 | 0.00716 | 0.378
2975807 | 지상 8층 | 지상 8층 | 2975762 | 716 | 0.189 | 0.00716 | 0.378
2975808 | 지상 8층 | 지상 8층 | 2975762 | 300 | 0.085 | 0.003 | 0.16
2975809 | 지상 8층 | 지상 8층 | 2975762 | 600 | 0.16 | 0.006 | 0.3
2975810 | 지상 8층 | 지상 8층 | 2975762 | 1100 | 0.285 | 0.011 | 0.56
2975815 | 지상 8층 | 지상 8층 | 2975762 | 741 | 0.19525 | 0.00741 | 0.3805
2975816 | 지상 8층 | 지상 8층 | 2975762 | 741 | 0.19525 | 0.00741 | 0.3805
2975817 | 지상 8층 | 지상 8층 | 2975762 | 716 | 0.189 | 0.00716 | 0.378
2975818 | 지상 8층 | 지상 8층 | 2975762 | 716 | 0.189 | 0.00716 | 0.378
2975819 | 지상 8층 | 지상 8층 | 2975762 | 300 | 0.085 | 0.003 | 0.16
2975820 | 지상 8층 | 지상 8층 | 2975762 | 600 | 0.16 | 0.006 | 0.3
2975821 | 지상 8층 | 지상 8층 | 2975762 | 1100 | 0.285 | 0.011 | 0.56
2975826 | 지상 8층 | 지상 8층 | 2975762 | 741 | 0.19525 | 0.00741 | 0.3805
2975827 | 지상 8층 | 지상 8층 | 2975762 | 741 | 0.19525 | 0.00741 | 0.3805
2975828 | 지상 8층 | 지상 8층 | 2975762 | 716 | 0.189 | 0.00716 | 0.378
2975829 | 지상 8층 | 지상 8층 | 2975762 | 716 | 0.189 | 0.00716 | 0.378
2975830 | 지상 8층 | 지상 8층 | 2975762 | 300 | 0.085 | 0.003 | 0.16
2975831 | 지상 8층 | 지상 8층 | 2975762 | 600 | 0.16 | 0.006 | 0.3
2975832 | 지상 8층 | 지상 8층 | 2975762 | 1100 | 0.285 | 0.011 | 0.56
2975837 | 지상 8층 | 지상 8층 | 2975762 | 741 | 0.19525 | 0.00741 | 0.3805
2975838 | 지상 8층 | 지상 8층 | 2975762 | 741 | 0.19525 | 0.00741 | 0.3805
2975839 | 지상 8층 | 지상 8층 | 2975762 | 716 | 0.189 | 0.00716 | 0.378
2975840 | 지상 8층 | 지상 8층 | 2975762 | 716 | 0.189 | 0.00716 | 0.378
2975841 | 지상 8층 | 지상 8층 | 2975762 | 300 | 0.085 | 0.003 | 0.16
2975842 | 지상 8층 | 지상 8층 | 2975762 | 600 | 0.16 | 0.006 | 0.3
2975843 | 지상 8층 | 지상 8층 | 2975762 | 1100 | 0.285 | 0.011 | 0.56
2975848 | 지상 8층 | 지상 8층 | 2975762 | 741 | 0.19525 | 0.00741 | 0.3805
2975849 | 지상 8층 | 지상 8층 | 2975762 | 741 | 0.19525 | 0.00741 | 0.3805
2975850 | 지상 8층 | 지상 8층 | 2975762 | 716 | 0.189 | 0.00716 | 0.378
2975851 | 지상 8층 | 지상 8층 | 2975762 | 716 | 0.189 | 0.00716 | 0.378
2975852 | 지상 8층 | 지상 8층 | 2975762 | 300 | 0.085 | 0.003 | 0.16
2975853 | 지상 8층 | 지상 8층 | 2975762 | 600 | 0.16 | 0.006 | 0.3
2975854 | 지상 8층 | 지상 8층 | 2975762 | 1100 | 0.285 | 0.011 | 0.56
2975859 | 지상 8층 | 지상 8층 | 2975762 | 1000 | 0.26 | 0.01 | 0.52
2975860 | 지상 8층 | 지상 8층 | 2975762 | 801 | 0.21025 | 0.00801 | 0.4105
2975861 | 지상 8층 | 지상 8층 | 2975762 | 776 | 0.204 | 0.00776 | 0.408
2975862 | 지상 8층 | 지상 8층 | 2975762 | 776 | 0.204 | 0.00776 | 0.408
2975863 | 지상 8층 | 지상 8층 | 2975762 | 300 | 0.085 | 0.003 | 0.16
2975864 | 지상 8층 | 지상 8층 | 2975762 | 600 | 0.16 | 0.006 | 0.3
2975865 | 지상 8층 | 지상 8층 | 2975762 | 1100 | 0.285 | 0.011 | 0.56
2975870 | 지상 8층 | 지상 8층 | 2975762 | 801 | 0.21025 | 0.00801 | 0.4105
2975871 | 지상 8층 | 지상 8층 | 2975762 | 1000 | 0.26 | 0.01 | 0.52
2975872 | 지상 8층 | 지상 8층 | 2975762 | 1000 | 0.26 | 0.01 | 0.52
2975873 | 지상 8층 | 지상 8층 | 2975762 | 1000 | 0.26 | 0.01 | 0.52
2975874 | 지상 8층 | 지상 8층 | 2975762 | 300 | 0.085 | 0.003 | 0.16
2975875 | 지상 8층 | 지상 8층 | 2975762 | 600 | 0.16 | 0.006 | 0.3
2975876 | 지상 8층 | 지상 8층 | 2975762 | 1100 | 0.285 | 0.011 | 0.56
2975881 | 지상 8층 | 지상 8층 | 2975762 | 741 | 0.19525 | 0.00741 | 0.3805
2975882 | 지상 8층 | 지상 8층 | 2975762 | 741 | 0.19525 | 0.00741 | 0.3805
2975883 | 지상 8층 | 지상 8층 | 2975762 | 716 | 0.189 | 0.00716 | 0.378
2975884 | 지상 8층 | 지상 8층 | 2975762 | 716 | 0.189 | 0.00716 | 0.378
2975885 | 지상 8층 | 지상 8층 | 2975762 | 300 | 0.085 | 0.003 | 0.16
2975886 | 지상 8층 | 지상 8층 | 2975762 | 600 | 0.16 | 0.006 | 0.3
2975887 | 지상 8층 | 지상 8층 | 2975762 | 1100 | 0.285 | 0.011 | 0.56
2975892 | 지상 8층 | 지상 8층 | 2975762 | 741 | 0.19525 | 0.00741 | 0.3805
2975893 | 지상 8층 | 지상 8층 | 2975762 | 741 | 0.19525 | 0.00741 | 0.3805
2975894 | 지상 8층 | 지상 8층 | 2975762 | 716 | 0.189 | 0.00716 | 0.378
2975895 | 지상 8층 | 지상 8층 | 2975762 | 716 | 0.189 | 0.00716 | 0.378
2975896 | 지상 8층 | 지상 8층 | 2975762 | 300 | 0.085 | 0.003 | 0.16
2975897 | 지상 8층 | 지상 8층 | 2975762 | 600 | 0.16 | 0.006 | 0.3
2975898 | 지상 8층 | 지상 8층 | 2975762 | 1100 | 0.285 | 0.011 | 0.56
2975903 | 지상 8층 | 지상 8층 | 2975762 | 741 | 0.19525 | 0.00741 | 0.3805
2975904 | 지상 8층 | 지상 8층 | 2975762 | 741 | 0.19525 | 0.00741 | 0.3805
2975905 | 지상 8층 | 지상 8층 | 2975762 | 716 | 0.189 | 0.00716 | 0.378
2975906 | 지상 8층 | 지상 8층 | 2975762 | 716 | 0.189 | 0.00716 | 0.378
2975907 | 지상 8층 | 지상 8층 | 2975762 | 300 | 0.085 | 0.003 | 0.16
2975908 | 지상 8층 | 지상 8층 | 2975762 | 600 | 0.16 | 0.006 | 0.3
2975909 | 지상 8층 | 지상 8층 | 2975762 | 1100 | 0.285 | 0.011 | 0.56
2975914 | 지상 8층 | 지상 8층 | 2975762 | 1000 | 0.26 | 0.01 | 0.52
2975915 | 지상 8층 | 지상 8층 | 2975762 | 801 | 0.21025 | 0.00801 | 0.4105
2975916 | 지상 8층 | 지상 8층 | 2975762 | 776 | 0.204 | 0.00776 | 0.408
2975917 | 지상 8층 | 지상 8층 | 2975762 | 776 | 0.204 | 0.00776 | 0.408
2975918 | 지상 8층 | 지상 8층 | 2975762 | 300 | 0.085 | 0.003 | 0.16
2975919 | 지상 8층 | 지상 8층 | 2975762 | 600 | 0.16 | 0.006 | 0.3
2975920 | 지상 8층 | 지상 8층 | 2975762 | 1100 | 0.285 | 0.011 | 0.56
2975925 | 지상 8층 | 지상 8층 | 2975762 | 814 | 0.2135 | 0.00814 | 0.417
2975926 | 지상 8층 | 지상 8층 | 2975762 | 1000 | 0.26 | 0.01 | 0.52
2975927 | 지상 8층 | 지상 8층 | 2975762 | 1000 | 0.26 | 0.01 | 0.52
2975928 | 지상 8층 | 지상 8층 | 2975762 | 1000 | 0.26 | 0.01 | 0.52
2975929 | 지상 8층 | 지상 8층 | 2975762 | 300 | 0.085 | 0.003 | 0.16
2975930 | 지상 8층 | 지상 8층 | 2975762 | 600 | 0.16 | 0.006 | 0.3
2975931 | 지상 8층 | 지상 8층 | 2975762 | 1100 | 0.285 | 0.011 | 0.56
2975936 | 지상 8층 | 지상 8층 | 2975762 | 754 | 0.1985 | 0.00754 | 0.387
2975937 | 지상 8층 | 지상 8층 | 2975762 | 754 | 0.1985 | 0.00754 | 0.387
2975938 | 지상 8층 | 지상 8층 | 2975762 | 729 | 0.19225 | 0.00729 | 0.3845
2975939 | 지상 8층 | 지상 8층 | 2975762 | 729 | 0.19225 | 0.00729 | 0.3845
2975940 | 지상 8층 | 지상 8층 | 2975762 | 300 | 0.085 | 0.003 | 0.16
2975941 | 지상 8층 | 지상 8층 | 2975762 | 600 | 0.16 | 0.006 | 0.3
2975942 | 지상 8층 | 지상 8층 | 2975762 | 1100 | 0.285 | 0.011 | 0.56
2975947 | 지상 8층 | 지상 8층 | 2975762 | 754 | 0.1985 | 0.00754 | 0.387
2975948 | 지상 8층 | 지상 8층 | 2975762 | 754 | 0.1985 | 0.00754 | 0.387
2975949 | 지상 8층 | 지상 8층 | 2975762 | 729 | 0.19225 | 0.00729 | 0.3845
2975950 | 지상 8층 | 지상 8층 | 2975762 | 729 | 0.19225 | 0.00729 | 0.3845
2975951 | 지상 8층 | 지상 8층 | 2975762 | 300 | 0.085 | 0.003 | 0.16
2975952 | 지상 8층 | 지상 8층 | 2975762 | 600 | 0.16 | 0.006 | 0.3
2975953 | 지상 8층 | 지상 8층 | 2975762 | 1100 | 0.285 | 0.011 | 0.56
2975958 | 지상 8층 | 지상 8층 | 2975762 | 754 | 0.1985 | 0.00754 | 0.387
2975959 | 지상 8층 | 지상 8층 | 2975762 | 754 | 0.1985 | 0.00754 | 0.387
2975960 | 지상 8층 | 지상 8층 | 2975762 | 729 | 0.19225 | 0.00729 | 0.3845
2975961 | 지상 8층 | 지상 8층 | 2975762 | 729 | 0.19225 | 0.00729 | 0.3845
2975962 | 지상 8층 | 지상 8층 | 2975762 | 300 | 0.085 | 0.003 | 0.16
2975963 | 지상 8층 | 지상 8층 | 2975762 | 600 | 0.16 | 0.006 | 0.3
2975964 | 지상 8층 | 지상 8층 | 2975762 | 1100 | 0.285 | 0.011 | 0.56
2975969 | 지상 8층 | 지상 8층 | 2975762 | 725 | 0.19125 | 0.00725 | 0.3725
2975970 | 지상 8층 | 지상 8층 | 2975762 | 754 | 0.1985 | 0.00754 | 0.387
2975971 | 지상 8층 | 지상 8층 | 2975762 | 729 | 0.19225 | 0.00729 | 0.3845
2975972 | 지상 8층 | 지상 8층 | 2975762 | 729 | 0.19225 | 0.00729 | 0.3845
2975973 | 지상 8층 | 지상 8층 | 2975762 | 300 | 0.085 | 0.003 | 0.16
2975974 | 지상 8층 | 지상 8층 | 2975762 | 600 | 0.16 | 0.006 | 0.3
2975975 | 지상 8층 | 지상 8층 | 2975762 | 1100 | 0.285 | 0.011 | 0.56
2975980 | 지상 8층 | 지상 8층 | 2975762 | 667 | 0.17675 | 0.00667 | 0.3435
2975981 | 지상 8층 | 지상 8층 | 2975762 | 727 | 0.19175 | 0.00727 | 0.3735
2975982 | 지상 8층 | 지상 8층 | 2975762 | 702 | 0.1855 | 0.00702 | 0.371
2975983 | 지상 8층 | 지상 8층 | 2975762 | 702 | 0.1855 | 0.00702 | 0.371
2975984 | 지상 8층 | 지상 8층 | 2975762 | 650 | 0.1725 | 0.0065 | 0.345
2975989 | 지상 8층 | 지상 8층 | 2975762 | 741 | 0.19525 | 0.00741 | 0.3805
2975990 | 지상 8층 | 지상 8층 | 2975762 | 741 | 0.19525 | 0.00741 | 0.3805
2975991 | 지상 8층 | 지상 8층 | 2975762 | 716 | 0.189 | 0.00716 | 0.378
2975992 | 지상 8층 | 지상 8층 | 2975762 | 716 | 0.189 | 0.00716 | 0.378
2975993 | 지상 8층 | 지상 8층 | 2975762 | 650 | 0.1725 | 0.0065 | 0.345
2975998 | 지상 8층 | 지상 8층 | 2975762 | 741 | 0.19525 | 0.00741 | 0.3805
2975999 | 지상 8층 | 지상 8층 | 2975762 | 741 | 0.19525 | 0.00741 | 0.3805
2976000 | 지상 8층 | 지상 8층 | 2975762 | 716 | 0.189 | 0.00716 | 0.378
2976001 | 지상 8층 | 지상 8층 | 2975762 | 716 | 0.189 | 0.00716 | 0.378
2976002 | 지상 8층 | 지상 8층 | 2975762 | 650 | 0.1725 | 0.0065 | 0.345
2976007 | 지상 8층 | 지상 8층 | 2975762 | 741 | 0.19525 | 0.00741 | 0.3805
2976008 | 지상 8층 | 지상 8층 | 2975762 | 741 | 0.19525 | 0.00741 | 0.3805
2976009 | 지상 8층 | 지상 8층 | 2975762 | 716 | 0.189 | 0.00716 | 0.378
2976010 | 지상 8층 | 지상 8층 | 2975762 | 716 | 0.189 | 0.00716 | 0.378
2976011 | 지상 8층 | 지상 8층 | 2975762 | 650 | 0.1725 | 0.0065 | 0.345
2976016 | 지상 8층 | 지상 8층 | 2975762 | 741 | 0.19525 | 0.00741 | 0.3805
2976017 | 지상 8층 | 지상 8층 | 2975762 | 741 | 0.19525 | 0.00741 | 0.3805
2976018 | 지상 8층 | 지상 8층 | 2975762 | 716 | 0.189 | 0.00716 | 0.378
2976019 | 지상 8층 | 지상 8층 | 2975762 | 716 | 0.189 | 0.00716 | 0.378
2976020 | 지상 8층 | 지상 8층 | 2975762 | 650 | 0.1725 | 0.0065 | 0.345
2976025 | 지상 8층 | 지상 8층 | 2975762 | 741 | 0.19525 | 0.00741 | 0.3805
2976026 | 지상 8층 | 지상 8층 | 2975762 | 741 | 0.19525 | 0.00741 | 0.3805
2976027 | 지상 8층 | 지상 8층 | 2975762 | 716 | 0.189 | 0.00716 | 0.378
2976028 | 지상 8층 | 지상 8층 | 2975762 | 716 | 0.189 | 0.00716 | 0.378
2976029 | 지상 8층 | 지상 8층 | 2975762 | 650 | 0.1725 | 0.0065 | 0.345
2976034 | 지상 8층 | 지상 8층 | 2975762 | 801 | 0.21025 | 0.00801 | 0.4105
2976035 | 지상 8층 | 지상 8층 | 2975762 | 741 | 0.19525 | 0.00741 | 0.3805
2976036 | 지상 8층 | 지상 8층 | 2975762 | 716 | 0.189 | 0.00716 | 0.378
2976037 | 지상 8층 | 지상 8층 | 2975762 | 716 | 0.189 | 0.00716 | 0.378
2976038 | 지상 8층 | 지상 8층 | 2975762 | 650 | 0.1725 | 0.0065 | 0.345
2976043 | 지상 8층 | 지상 8층 | 2975762 | 741 | 0.19525 | 0.00741 | 0.3805
2976044 | 지상 8층 | 지상 8층 | 2975762 | 801 | 0.21025 | 0.00801 | 0.4105
2976045 | 지상 8층 | 지상 8층 | 2975762 | 776 | 0.204 | 0.00776 | 0.408
2976046 | 지상 8층 | 지상 8층 | 2975762 | 776 | 0.204 | 0.00776 | 0.408
2976047 | 지상 8층 | 지상 8층 | 2975762 | 650 | 0.1725 | 0.0065 | 0.345
2976052 | 지상 8층 | 지상 8층 | 2975762 | 741 | 0.19525 | 0.00741 | 0.3805
2976053 | 지상 8층 | 지상 8층 | 2975762 | 741 | 0.19525 | 0.00741 | 0.3805
2976054 | 지상 8층 | 지상 8층 | 2975762 | 716 | 0.189 | 0.00716 | 0.378
2976055 | 지상 8층 | 지상 8층 | 2975762 | 716 | 0.189 | 0.00716 | 0.378
2976056 | 지상 8층 | 지상 8층 | 2975762 | 650 | 0.1725 | 0.0065 | 0.345
2976061 | 지상 8층 | 지상 8층 | 2975762 | 741 | 0.19525 | 0.00741 | 0.3805
2976062 | 지상 8층 | 지상 8층 | 2975762 | 741 | 0.19525 | 0.00741 | 0.3805
2976063 | 지상 8층 | 지상 8층 | 2975762 | 716 | 0.189 | 0.00716 | 0.378
2976064 | 지상 8층 | 지상 8층 | 2975762 | 716 | 0.189 | 0.00716 | 0.378
2976065 | 지상 8층 | 지상 8층 | 2975762 | 650 | 0.1725 | 0.0065 | 0.345
2976070 | 지상 8층 | 지상 8층 | 2975762 | 801 | 0.21025 | 0.00801 | 0.4105
2976071 | 지상 8층 | 지상 8층 | 2975762 | 741 | 0.19525 | 0.00741 | 0.3805
2976072 | 지상 8층 | 지상 8층 | 2975762 | 716 | 0.189 | 0.00716 | 0.378
2976073 | 지상 8층 | 지상 8층 | 2975762 | 716 | 0.189 | 0.00716 | 0.378
2976074 | 지상 8층 | 지상 8층 | 2975762 | 650 | 0.1725 | 0.0065 | 0.345
2976079 | 지상 8층 | 지상 8층 | 2975762 | 754 | 0.1985 | 0.00754 | 0.387
2976080 | 지상 8층 | 지상 8층 | 2975762 | 814 | 0.2135 | 0.00814 | 0.417
2976081 | 지상 8층 | 지상 8층 | 2975762 | 789 | 0.20725 | 0.00789 | 0.4145
2976082 | 지상 8층 | 지상 8층 | 2975762 | 789 | 0.20725 | 0.00789 | 0.4145
2976083 | 지상 8층 | 지상 8층 | 2975762 | 650 | 0.1725 | 0.0065 | 0.345
2976088 | 지상 8층 | 지상 8층 | 2975762 | 754 | 0.1985 | 0.00754 | 0.387
2976089 | 지상 8층 | 지상 8층 | 2975762 | 754 | 0.1985 | 0.00754 | 0.387
2976090 | 지상 8층 | 지상 8층 | 2975762 | 729 | 0.19225 | 0.00729 | 0.3845
2976091 | 지상 8층 | 지상 8층 | 2975762 | 729 | 0.19225 | 0.00729 | 0.3845
2976092 | 지상 8층 | 지상 8층 | 2975762 | 650 | 0.1725 | 0.0065 | 0.345
2976097 | 지상 8층 | 지상 8층 | 2975762 | 754 | 0.1985 | 0.00754 | 0.387
2976098 | 지상 8층 | 지상 8층 | 2975762 | 754 | 0.1985 | 0.00754 | 0.387
2976099 | 지상 8층 | 지상 8층 | 2975762 | 729 | 0.19225 | 0.00729 | 0.3845
2976100 | 지상 8층 | 지상 8층 | 2975762 | 729 | 0.19225 | 0.00729 | 0.3845
2976101 | 지상 8층 | 지상 8층 | 2975762 | 650 | 0.1725 | 0.0065 | 0.345
2976106 | 지상 8층 | 지상 8층 | 2975762 | 754 | 0.1985 | 0.00754 | 0.387
2976107 | 지상 8층 | 지상 8층 | 2975762 | 754 | 0.1985 | 0.00754 | 0.387
2976108 | 지상 8층 | 지상 8층 | 2975762 | 729 | 0.19225 | 0.00729 | 0.3845
2976109 | 지상 8층 | 지상 8층 | 2975762 | 729 | 0.19225 | 0.00729 | 0.3845
2976110 | 지상 8층 | 지상 8층 | 2975762 | 650 | 0.1725 | 0.0065 | 0.345
2976115 | 지상 8층 | 지상 8층 | 2975762 | 725 | 0.19125 | 0.00725 | 0.3725
2976116 | 지상 8층 | 지상 8층 | 2975762 | 700 | 0.185 | 0.007 | 0.37
2976117 | 지상 8층 | 지상 8층 | 2975762 | 700 | 0.185 | 0.007 | 0.37
2976118 | 지상 8층 | 지상 8층 | 2975762 | 908.395 | 0.237099 | 0.00908395 | 0.464197
2976119 | 지상 8층 | 지상 8층 | 2975762 | 650 | 0.1725 | 0.0065 | 0.345
2976124 | 지상 9층 | 지상 9층 | 2976122 | 912.605 | 0.238151 | 0.00912605 | 0.476303
2976125 | 지상 9층 | 지상 9층 | 2976122 | 726.395 | 0.191599 | 0.00726395 | 0.373197
2976127 | 지상 9층 | 지상 9층 | 2976122 | 1600 | 0.41 | 0.016 | 0.81
2976131 | 지상 9층 | 지상 9층 | 2976122 | 300 | 0.085 | 0.003 | 0.16
2976132 | 지상 9층 | 지상 9층 | 2976122 | 701.395 | 0.185349 | 0.00701395 | 0.370697
2976136 | 지상 9층 | 지상 9층 | 2976122 | 600 | 0.16 | 0.006 | 0.3
2976137 | 지상 9층 | 지상 9층 | 2976122 | 701.395 | 0.185349 | 0.00701395 | 0.370697
2976142 | 지상 9층 | 지상 9층 | 2976122 | 727 | 0.19175 | 0.00727 | 0.3735
2976143 | 지상 9층 | 지상 9층 | 2976122 | 912.605 | 0.238151 | 0.00912605 | 0.476303
2976144 | 지상 9층 | 지상 9층 | 2976122 | 912.605 | 0.238151 | 0.00912605 | 0.476303
2976145 | 지상 9층 | 지상 9층 | 2976122 | 912.605 | 0.238151 | 0.00912605 | 0.476303
2976146 | 지상 9층 | 지상 9층 | 2976122 | 300 | 0.085 | 0.003 | 0.16
2976147 | 지상 9층 | 지상 9층 | 2976122 | 600 | 0.16 | 0.006 | 0.3
2976148 | 지상 9층 | 지상 9층 | 2976122 | 1600 | 0.41 | 0.016 | 0.81
2976153 | 지상 9층 | 지상 9층 | 2976122 | 741 | 0.19525 | 0.00741 | 0.3805
2976154 | 지상 9층 | 지상 9층 | 2976122 | 667 | 0.17675 | 0.00667 | 0.3435
2976155 | 지상 9층 | 지상 9층 | 2976122 | 642 | 0.1705 | 0.00642 | 0.341
2976156 | 지상 9층 | 지상 9층 | 2976122 | 642 | 0.1705 | 0.00642 | 0.341
2976157 | 지상 9층 | 지상 9층 | 2976122 | 300 | 0.085 | 0.003 | 0.16
2976158 | 지상 9층 | 지상 9층 | 2976122 | 600 | 0.16 | 0.006 | 0.3
2976159 | 지상 9층 | 지상 9층 | 2976122 | 1600 | 0.41 | 0.016 | 0.81
2976164 | 지상 9층 | 지상 9층 | 2976122 | 741 | 0.19525 | 0.00741 | 0.3805
2976165 | 지상 9층 | 지상 9층 | 2976122 | 741 | 0.19525 | 0.00741 | 0.3805
2976166 | 지상 9층 | 지상 9층 | 2976122 | 716 | 0.189 | 0.00716 | 0.378
2976167 | 지상 9층 | 지상 9층 | 2976122 | 716 | 0.189 | 0.00716 | 0.378
2976168 | 지상 9층 | 지상 9층 | 2976122 | 300 | 0.085 | 0.003 | 0.16
2976169 | 지상 9층 | 지상 9층 | 2976122 | 600 | 0.16 | 0.006 | 0.3
2976170 | 지상 9층 | 지상 9층 | 2976122 | 1600 | 0.41 | 0.016 | 0.81
2976175 | 지상 9층 | 지상 9층 | 2976122 | 741 | 0.19525 | 0.00741 | 0.3805
2976176 | 지상 9층 | 지상 9층 | 2976122 | 741 | 0.19525 | 0.00741 | 0.3805
2976177 | 지상 9층 | 지상 9층 | 2976122 | 716 | 0.189 | 0.00716 | 0.378
2976178 | 지상 9층 | 지상 9층 | 2976122 | 716 | 0.189 | 0.00716 | 0.378
2976179 | 지상 9층 | 지상 9층 | 2976122 | 300 | 0.085 | 0.003 | 0.16
2976180 | 지상 9층 | 지상 9층 | 2976122 | 600 | 0.16 | 0.006 | 0.3
2976181 | 지상 9층 | 지상 9층 | 2976122 | 1600 | 0.41 | 0.016 | 0.81
2976186 | 지상 9층 | 지상 9층 | 2976122 | 741 | 0.19525 | 0.00741 | 0.3805
2976187 | 지상 9층 | 지상 9층 | 2976122 | 741 | 0.19525 | 0.00741 | 0.3805
2976188 | 지상 9층 | 지상 9층 | 2976122 | 716 | 0.189 | 0.00716 | 0.378
2976189 | 지상 9층 | 지상 9층 | 2976122 | 716 | 0.189 | 0.00716 | 0.378
2976190 | 지상 9층 | 지상 9층 | 2976122 | 300 | 0.085 | 0.003 | 0.16
2976191 | 지상 9층 | 지상 9층 | 2976122 | 600 | 0.16 | 0.006 | 0.3
2976192 | 지상 9층 | 지상 9층 | 2976122 | 1600 | 0.41 | 0.016 | 0.81
2976197 | 지상 9층 | 지상 9층 | 2976122 | 741 | 0.19525 | 0.00741 | 0.3805
2976198 | 지상 9층 | 지상 9층 | 2976122 | 741 | 0.19525 | 0.00741 | 0.3805
2976199 | 지상 9층 | 지상 9층 | 2976122 | 716 | 0.189 | 0.00716 | 0.378
2976200 | 지상 9층 | 지상 9층 | 2976122 | 716 | 0.189 | 0.00716 | 0.378
2976201 | 지상 9층 | 지상 9층 | 2976122 | 300 | 0.085 | 0.003 | 0.16
2976202 | 지상 9층 | 지상 9층 | 2976122 | 600 | 0.16 | 0.006 | 0.3
2976203 | 지상 9층 | 지상 9층 | 2976122 | 1600 | 0.41 | 0.016 | 0.81
2976208 | 지상 9층 | 지상 9층 | 2976122 | 741 | 0.19525 | 0.00741 | 0.3805
2976209 | 지상 9층 | 지상 9층 | 2976122 | 741 | 0.19525 | 0.00741 | 0.3805
2976210 | 지상 9층 | 지상 9층 | 2976122 | 716 | 0.189 | 0.00716 | 0.378
2976211 | 지상 9층 | 지상 9층 | 2976122 | 716 | 0.189 | 0.00716 | 0.378
2976212 | 지상 9층 | 지상 9층 | 2976122 | 300 | 0.085 | 0.003 | 0.16
2976213 | 지상 9층 | 지상 9층 | 2976122 | 600 | 0.16 | 0.006 | 0.3
2976214 | 지상 9층 | 지상 9층 | 2976122 | 1600 | 0.41 | 0.016 | 0.81
2976219 | 지상 9층 | 지상 9층 | 2976122 | 1000 | 0.26 | 0.01 | 0.52
2976220 | 지상 9층 | 지상 9층 | 2976122 | 801 | 0.21025 | 0.00801 | 0.4105
2976221 | 지상 9층 | 지상 9층 | 2976122 | 776 | 0.204 | 0.00776 | 0.408
2976222 | 지상 9층 | 지상 9층 | 2976122 | 776 | 0.204 | 0.00776 | 0.408
2976223 | 지상 9층 | 지상 9층 | 2976122 | 300 | 0.085 | 0.003 | 0.16
2976224 | 지상 9층 | 지상 9층 | 2976122 | 600 | 0.16 | 0.006 | 0.3
2976225 | 지상 9층 | 지상 9층 | 2976122 | 1600 | 0.41 | 0.016 | 0.81
2976230 | 지상 9층 | 지상 9층 | 2976122 | 801 | 0.21025 | 0.00801 | 0.4105
2976231 | 지상 9층 | 지상 9층 | 2976122 | 1000 | 0.26 | 0.01 | 0.52
2976232 | 지상 9층 | 지상 9층 | 2976122 | 1000 | 0.26 | 0.01 | 0.52
2976233 | 지상 9층 | 지상 9층 | 2976122 | 1000 | 0.26 | 0.01 | 0.52
2976234 | 지상 9층 | 지상 9층 | 2976122 | 300 | 0.085 | 0.003 | 0.16
2976235 | 지상 9층 | 지상 9층 | 2976122 | 600 | 0.16 | 0.006 | 0.3
2976236 | 지상 9층 | 지상 9층 | 2976122 | 1600 | 0.41 | 0.016 | 0.81
2976241 | 지상 9층 | 지상 9층 | 2976122 | 741 | 0.19525 | 0.00741 | 0.3805
2976242 | 지상 9층 | 지상 9층 | 2976122 | 741 | 0.19525 | 0.00741 | 0.3805
2976243 | 지상 9층 | 지상 9층 | 2976122 | 716 | 0.189 | 0.00716 | 0.378
2976244 | 지상 9층 | 지상 9층 | 2976122 | 716 | 0.189 | 0.00716 | 0.378
2976245 | 지상 9층 | 지상 9층 | 2976122 | 300 | 0.085 | 0.003 | 0.16
2976246 | 지상 9층 | 지상 9층 | 2976122 | 600 | 0.16 | 0.006 | 0.3
2976247 | 지상 9층 | 지상 9층 | 2976122 | 1600 | 0.41 | 0.016 | 0.81
2976252 | 지상 9층 | 지상 9층 | 2976122 | 741 | 0.19525 | 0.00741 | 0.3805
2976253 | 지상 9층 | 지상 9층 | 2976122 | 741 | 0.19525 | 0.00741 | 0.3805
2976254 | 지상 9층 | 지상 9층 | 2976122 | 716 | 0.189 | 0.00716 | 0.378
2976255 | 지상 9층 | 지상 9층 | 2976122 | 716 | 0.189 | 0.00716 | 0.378
2976256 | 지상 9층 | 지상 9층 | 2976122 | 300 | 0.085 | 0.003 | 0.16
2976257 | 지상 9층 | 지상 9층 | 2976122 | 600 | 0.16 | 0.006 | 0.3
2976258 | 지상 9층 | 지상 9층 | 2976122 | 1600 | 0.41 | 0.016 | 0.81
2976263 | 지상 9층 | 지상 9층 | 2976122 | 741 | 0.19525 | 0.00741 | 0.3805
2976264 | 지상 9층 | 지상 9층 | 2976122 | 741 | 0.19525 | 0.00741 | 0.3805
2976265 | 지상 9층 | 지상 9층 | 2976122 | 716 | 0.189 | 0.00716 | 0.378
2976266 | 지상 9층 | 지상 9층 | 2976122 | 716 | 0.189 | 0.00716 | 0.378
2976267 | 지상 9층 | 지상 9층 | 2976122 | 300 | 0.085 | 0.003 | 0.16
2976268 | 지상 9층 | 지상 9층 | 2976122 | 600 | 0.16 | 0.006 | 0.3
2976269 | 지상 9층 | 지상 9층 | 2976122 | 1600 | 0.41 | 0.016 | 0.81
2976274 | 지상 9층 | 지상 9층 | 2976122 | 1000 | 0.26 | 0.01 | 0.52
2976275 | 지상 9층 | 지상 9층 | 2976122 | 801 | 0.21025 | 0.00801 | 0.4105
2976276 | 지상 9층 | 지상 9층 | 2976122 | 776 | 0.204 | 0.00776 | 0.408
2976277 | 지상 9층 | 지상 9층 | 2976122 | 776 | 0.204 | 0.00776 | 0.408
2976278 | 지상 9층 | 지상 9층 | 2976122 | 300 | 0.085 | 0.003 | 0.16
2976279 | 지상 9층 | 지상 9층 | 2976122 | 600 | 0.16 | 0.006 | 0.3
2976280 | 지상 9층 | 지상 9층 | 2976122 | 1600 | 0.41 | 0.016 | 0.81
2976285 | 지상 9층 | 지상 9층 | 2976122 | 814 | 0.2135 | 0.00814 | 0.417
2976286 | 지상 9층 | 지상 9층 | 2976122 | 1000 | 0.26 | 0.01 | 0.52
2976287 | 지상 9층 | 지상 9층 | 2976122 | 1000 | 0.26 | 0.01 | 0.52
2976288 | 지상 9층 | 지상 9층 | 2976122 | 1000 | 0.26 | 0.01 | 0.52
2976289 | 지상 9층 | 지상 9층 | 2976122 | 300 | 0.085 | 0.003 | 0.16
2976290 | 지상 9층 | 지상 9층 | 2976122 | 600 | 0.16 | 0.006 | 0.3
2976291 | 지상 9층 | 지상 9층 | 2976122 | 1600 | 0.41 | 0.016 | 0.81
2976296 | 지상 9층 | 지상 9층 | 2976122 | 754 | 0.1985 | 0.00754 | 0.387
2976297 | 지상 9층 | 지상 9층 | 2976122 | 754 | 0.1985 | 0.00754 | 0.387
2976298 | 지상 9층 | 지상 9층 | 2976122 | 729 | 0.19225 | 0.00729 | 0.3845
2976299 | 지상 9층 | 지상 9층 | 2976122 | 729 | 0.19225 | 0.00729 | 0.3845
2976300 | 지상 9층 | 지상 9층 | 2976122 | 300 | 0.085 | 0.003 | 0.16
2976301 | 지상 9층 | 지상 9층 | 2976122 | 600 | 0.16 | 0.006 | 0.3
2976302 | 지상 9층 | 지상 9층 | 2976122 | 1600 | 0.41 | 0.016 | 0.81
2976307 | 지상 9층 | 지상 9층 | 2976122 | 754 | 0.1985 | 0.00754 | 0.387
2976308 | 지상 9층 | 지상 9층 | 2976122 | 754 | 0.1985 | 0.00754 | 0.387
2976309 | 지상 9층 | 지상 9층 | 2976122 | 729 | 0.19225 | 0.00729 | 0.3845
2976310 | 지상 9층 | 지상 9층 | 2976122 | 729 | 0.19225 | 0.00729 | 0.3845
2976311 | 지상 9층 | 지상 9층 | 2976122 | 300 | 0.085 | 0.003 | 0.16
2976312 | 지상 9층 | 지상 9층 | 2976122 | 600 | 0.16 | 0.006 | 0.3
2976313 | 지상 9층 | 지상 9층 | 2976122 | 1600 | 0.41 | 0.016 | 0.81
2976318 | 지상 9층 | 지상 9층 | 2976122 | 754 | 0.1985 | 0.00754 | 0.387
2976319 | 지상 9층 | 지상 9층 | 2976122 | 754 | 0.1985 | 0.00754 | 0.387
2976320 | 지상 9층 | 지상 9층 | 2976122 | 729 | 0.19225 | 0.00729 | 0.3845
2976321 | 지상 9층 | 지상 9층 | 2976122 | 729 | 0.19225 | 0.00729 | 0.3845
2976322 | 지상 9층 | 지상 9층 | 2976122 | 300 | 0.085 | 0.003 | 0.16
2976323 | 지상 9층 | 지상 9층 | 2976122 | 600 | 0.16 | 0.006 | 0.3
2976324 | 지상 9층 | 지상 9층 | 2976122 | 1600 | 0.41 | 0.016 | 0.81
2976329 | 지상 9층 | 지상 9층 | 2976122 | 725 | 0.19125 | 0.00725 | 0.3725
2976330 | 지상 9층 | 지상 9층 | 2976122 | 754 | 0.1985 | 0.00754 | 0.387
2976331 | 지상 9층 | 지상 9층 | 2976122 | 729 | 0.19225 | 0.00729 | 0.3845
2976332 | 지상 9층 | 지상 9층 | 2976122 | 729 | 0.19225 | 0.00729 | 0.3845
2976333 | 지상 9층 | 지상 9층 | 2976122 | 300 | 0.085 | 0.003 | 0.16
2976334 | 지상 9층 | 지상 9층 | 2976122 | 600 | 0.16 | 0.006 | 0.3
2976335 | 지상 9층 | 지상 9층 | 2976122 | 1600 | 0.41 | 0.016 | 0.81
2976340 | 지상 9층 | 지상 9층 | 2976122 | 667 | 0.17675 | 0.00667 | 0.3435
2976341 | 지상 9층 | 지상 9층 | 2976122 | 727 | 0.19175 | 0.00727 | 0.3735
2976342 | 지상 9층 | 지상 9층 | 2976122 | 702 | 0.1855 | 0.00702 | 0.371
2976343 | 지상 9층 | 지상 9층 | 2976122 | 702 | 0.1855 | 0.00702 | 0.371
2976344 | 지상 9층 | 지상 9층 | 2976122 | 650 | 0.1725 | 0.0065 | 0.345
2976349 | 지상 9층 | 지상 9층 | 2976122 | 741 | 0.19525 | 0.00741 | 0.3805
2976350 | 지상 9층 | 지상 9층 | 2976122 | 741 | 0.19525 | 0.00741 | 0.3805
2976351 | 지상 9층 | 지상 9층 | 2976122 | 716 | 0.189 | 0.00716 | 0.378
2976352 | 지상 9층 | 지상 9층 | 2976122 | 716 | 0.189 | 0.00716 | 0.378
2976353 | 지상 9층 | 지상 9층 | 2976122 | 650 | 0.1725 | 0.0065 | 0.345
2976358 | 지상 9층 | 지상 9층 | 2976122 | 741 | 0.19525 | 0.00741 | 0.3805
2976359 | 지상 9층 | 지상 9층 | 2976122 | 741 | 0.19525 | 0.00741 | 0.3805
2976360 | 지상 9층 | 지상 9층 | 2976122 | 716 | 0.189 | 0.00716 | 0.378
2976361 | 지상 9층 | 지상 9층 | 2976122 | 716 | 0.189 | 0.00716 | 0.378
2976362 | 지상 9층 | 지상 9층 | 2976122 | 650 | 0.1725 | 0.0065 | 0.345
2976367 | 지상 9층 | 지상 9층 | 2976122 | 741 | 0.19525 | 0.00741 | 0.3805
2976368 | 지상 9층 | 지상 9층 | 2976122 | 741 | 0.19525 | 0.00741 | 0.3805
2976369 | 지상 9층 | 지상 9층 | 2976122 | 716 | 0.189 | 0.00716 | 0.378
2976370 | 지상 9층 | 지상 9층 | 2976122 | 716 | 0.189 | 0.00716 | 0.378
2976371 | 지상 9층 | 지상 9층 | 2976122 | 650 | 0.1725 | 0.0065 | 0.345
2976376 | 지상 9층 | 지상 9층 | 2976122 | 741 | 0.19525 | 0.00741 | 0.3805
2976377 | 지상 9층 | 지상 9층 | 2976122 | 741 | 0.19525 | 0.00741 | 0.3805
2976378 | 지상 9층 | 지상 9층 | 2976122 | 716 | 0.189 | 0.00716 | 0.378
2976379 | 지상 9층 | 지상 9층 | 2976122 | 716 | 0.189 | 0.00716 | 0.378
2976380 | 지상 9층 | 지상 9층 | 2976122 | 650 | 0.1725 | 0.0065 | 0.345
2976385 | 지상 9층 | 지상 9층 | 2976122 | 741 | 0.19525 | 0.00741 | 0.3805
2976386 | 지상 9층 | 지상 9층 | 2976122 | 741 | 0.19525 | 0.00741 | 0.3805
2976387 | 지상 9층 | 지상 9층 | 2976122 | 716 | 0.189 | 0.00716 | 0.378
2976388 | 지상 9층 | 지상 9층 | 2976122 | 716 | 0.189 | 0.00716 | 0.378
2976389 | 지상 9층 | 지상 9층 | 2976122 | 650 | 0.1725 | 0.0065 | 0.345
2976394 | 지상 9층 | 지상 9층 | 2976122 | 801 | 0.21025 | 0.00801 | 0.4105
2976395 | 지상 9층 | 지상 9층 | 2976122 | 741 | 0.19525 | 0.00741 | 0.3805
2976396 | 지상 9층 | 지상 9층 | 2976122 | 716 | 0.189 | 0.00716 | 0.378
2976397 | 지상 9층 | 지상 9층 | 2976122 | 716 | 0.189 | 0.00716 | 0.378
2976398 | 지상 9층 | 지상 9층 | 2976122 | 650 | 0.1725 | 0.0065 | 0.345
2976403 | 지상 9층 | 지상 9층 | 2976122 | 741 | 0.19525 | 0.00741 | 0.3805
2976404 | 지상 9층 | 지상 9층 | 2976122 | 801 | 0.21025 | 0.00801 | 0.4105
2976405 | 지상 9층 | 지상 9층 | 2976122 | 776 | 0.204 | 0.00776 | 0.408
2976406 | 지상 9층 | 지상 9층 | 2976122 | 776 | 0.204 | 0.00776 | 0.408
2976407 | 지상 9층 | 지상 9층 | 2976122 | 650 | 0.1725 | 0.0065 | 0.345
2976412 | 지상 9층 | 지상 9층 | 2976122 | 741 | 0.19525 | 0.00741 | 0.3805
2976413 | 지상 9층 | 지상 9층 | 2976122 | 741 | 0.19525 | 0.00741 | 0.3805
2976414 | 지상 9층 | 지상 9층 | 2976122 | 716 | 0.189 | 0.00716 | 0.378
2976415 | 지상 9층 | 지상 9층 | 2976122 | 716 | 0.189 | 0.00716 | 0.378
2976416 | 지상 9층 | 지상 9층 | 2976122 | 650 | 0.1725 | 0.0065 | 0.345
2976421 | 지상 9층 | 지상 9층 | 2976122 | 741 | 0.19525 | 0.00741 | 0.3805
2976422 | 지상 9층 | 지상 9층 | 2976122 | 741 | 0.19525 | 0.00741 | 0.3805
2976423 | 지상 9층 | 지상 9층 | 2976122 | 716 | 0.189 | 0.00716 | 0.378
2976424 | 지상 9층 | 지상 9층 | 2976122 | 716 | 0.189 | 0.00716 | 0.378
2976425 | 지상 9층 | 지상 9층 | 2976122 | 650 | 0.1725 | 0.0065 | 0.345
2976430 | 지상 9층 | 지상 9층 | 2976122 | 801 | 0.21025 | 0.00801 | 0.4105
2976431 | 지상 9층 | 지상 9층 | 2976122 | 741 | 0.19525 | 0.00741 | 0.3805
2976432 | 지상 9층 | 지상 9층 | 2976122 | 716 | 0.189 | 0.00716 | 0.378
2976433 | 지상 9층 | 지상 9층 | 2976122 | 716 | 0.189 | 0.00716 | 0.378
2976434 | 지상 9층 | 지상 9층 | 2976122 | 650 | 0.1725 | 0.0065 | 0.345
2976439 | 지상 9층 | 지상 9층 | 2976122 | 754 | 0.1985 | 0.00754 | 0.387
2976440 | 지상 9층 | 지상 9층 | 2976122 | 814 | 0.2135 | 0.00814 | 0.417
2976441 | 지상 9층 | 지상 9층 | 2976122 | 789 | 0.20725 | 0.00789 | 0.4145
2976442 | 지상 9층 | 지상 9층 | 2976122 | 789 | 0.20725 | 0.00789 | 0.4145
2976443 | 지상 9층 | 지상 9층 | 2976122 | 650 | 0.1725 | 0.0065 | 0.345
2976448 | 지상 9층 | 지상 9층 | 2976122 | 754 | 0.1985 | 0.00754 | 0.387
2976449 | 지상 9층 | 지상 9층 | 2976122 | 754 | 0.1985 | 0.00754 | 0.387
2976450 | 지상 9층 | 지상 9층 | 2976122 | 729 | 0.19225 | 0.00729 | 0.3845
2976451 | 지상 9층 | 지상 9층 | 2976122 | 729 | 0.19225 | 0.00729 | 0.3845
2976452 | 지상 9층 | 지상 9층 | 2976122 | 650 | 0.1725 | 0.0065 | 0.345
2976457 | 지상 9층 | 지상 9층 | 2976122 | 754 | 0.1985 | 0.00754 | 0.387
2976458 | 지상 9층 | 지상 9층 | 2976122 | 754 | 0.1985 | 0.00754 | 0.387
2976459 | 지상 9층 | 지상 9층 | 2976122 | 729 | 0.19225 | 0.00729 | 0.3845
2976460 | 지상 9층 | 지상 9층 | 2976122 | 729 | 0.19225 | 0.00729 | 0.3845
2976461 | 지상 9층 | 지상 9층 | 2976122 | 650 | 0.1725 | 0.0065 | 0.345
2976466 | 지상 9층 | 지상 9층 | 2976122 | 754 | 0.1985 | 0.00754 | 0.387
2976467 | 지상 9층 | 지상 9층 | 2976122 | 754 | 0.1985 | 0.00754 | 0.387
2976468 | 지상 9층 | 지상 9층 | 2976122 | 729 | 0.19225 | 0.00729 | 0.3845
2976469 | 지상 9층 | 지상 9층 | 2976122 | 729 | 0.19225 | 0.00729 | 0.3845
2976470 | 지상 9층 | 지상 9층 | 2976122 | 650 | 0.1725 | 0.0065 | 0.345
2976475 | 지상 9층 | 지상 9층 | 2976122 | 725 | 0.19125 | 0.00725 | 0.3725
2976476 | 지상 9층 | 지상 9층 | 2976122 | 700 | 0.185 | 0.007 | 0.37
2976477 | 지상 9층 | 지상 9층 | 2976122 | 700 | 0.185 | 0.007 | 0.37
2976478 | 지상 9층 | 지상 9층 | 2976122 | 726.395 | 0.191599 | 0.00726395 | 0.373197
2976479 | 지상 9층 | 지상 9층 | 2976122 | 650 | 0.1725 | 0.0065 | 0.345
2976484 | 지상 10층 | 지상 10층 | 2976482 | 912.605 | 0.238151 | 0.00912605 | 0.476303
2976485 | 지상 10층 | 지상 10층 | 2976482 | 926.395 | 0.241599 | 0.00926395 | 0.473197
2976487 | 지상 10층 | 지상 10층 | 2976482 | 2100 | 0.535 | 0.021 | 1.06
2976491 | 지상 10층 | 지상 10층 | 2976482 | 300 | 0.085 | 0.003 | 0.16
2976492 | 지상 10층 | 지상 10층 | 2976482 | 901.395 | 0.235349 | 0.00901395 | 0.470697
2976496 | 지상 10층 | 지상 10층 | 2976482 | 600 | 0.16 | 0.006 | 0.3
2976497 | 지상 10층 | 지상 10층 | 2976482 | 901.395 | 0.235349 | 0.00901395 | 0.470697
2976502 | 지상 10층 | 지상 10층 | 2976482 | 727 | 0.19175 | 0.00727 | 0.3735
2976503 | 지상 10층 | 지상 10층 | 2976482 | 912.605 | 0.238151 | 0.00912605 | 0.476303
2976504 | 지상 10층 | 지상 10층 | 2976482 | 912.605 | 0.238151 | 0.00912605 | 0.476303
2976505 | 지상 10층 | 지상 10층 | 2976482 | 912.605 | 0.238151 | 0.00912605 | 0.476303
2976506 | 지상 10층 | 지상 10층 | 2976482 | 300 | 0.085 | 0.003 | 0.16
2976507 | 지상 10층 | 지상 10층 | 2976482 | 600 | 0.16 | 0.006 | 0.3
2976508 | 지상 10층 | 지상 10층 | 2976482 | 2100 | 0.535 | 0.021 | 1.06
2976513 | 지상 10층 | 지상 10층 | 2976482 | 741 | 0.19525 | 0.00741 | 0.3805
2976514 | 지상 10층 | 지상 10층 | 2976482 | 667 | 0.17675 | 0.00667 | 0.3435
2976515 | 지상 10층 | 지상 10층 | 2976482 | 642 | 0.1705 | 0.00642 | 0.341
2976516 | 지상 10층 | 지상 10층 | 2976482 | 642 | 0.1705 | 0.00642 | 0.341
2976517 | 지상 10층 | 지상 10층 | 2976482 | 300 | 0.085 | 0.003 | 0.16
2976518 | 지상 10층 | 지상 10층 | 2976482 | 600 | 0.16 | 0.006 | 0.3
2976519 | 지상 10층 | 지상 10층 | 2976482 | 2100 | 0.535 | 0.021 | 1.06
2976524 | 지상 10층 | 지상 10층 | 2976482 | 741 | 0.19525 | 0.00741 | 0.3805
2976525 | 지상 10층 | 지상 10층 | 2976482 | 741 | 0.19525 | 0.00741 | 0.3805
2976526 | 지상 10층 | 지상 10층 | 2976482 | 716 | 0.189 | 0.00716 | 0.378
2976527 | 지상 10층 | 지상 10층 | 2976482 | 716 | 0.189 | 0.00716 | 0.378
2976528 | 지상 10층 | 지상 10층 | 2976482 | 300 | 0.085 | 0.003 | 0.16
2976529 | 지상 10층 | 지상 10층 | 2976482 | 600 | 0.16 | 0.006 | 0.3
2976530 | 지상 10층 | 지상 10층 | 2976482 | 2100 | 0.535 | 0.021 | 1.06
2976535 | 지상 10층 | 지상 10층 | 2976482 | 741 | 0.19525 | 0.00741 | 0.3805
2976536 | 지상 10층 | 지상 10층 | 2976482 | 741 | 0.19525 | 0.00741 | 0.3805
2976537 | 지상 10층 | 지상 10층 | 2976482 | 716 | 0.189 | 0.00716 | 0.378
2976538 | 지상 10층 | 지상 10층 | 2976482 | 716 | 0.189 | 0.00716 | 0.378
2976539 | 지상 10층 | 지상 10층 | 2976482 | 300 | 0.085 | 0.003 | 0.16
2976540 | 지상 10층 | 지상 10층 | 2976482 | 600 | 0.16 | 0.006 | 0.3
2976541 | 지상 10층 | 지상 10층 | 2976482 | 2100 | 0.535 | 0.021 | 1.06
2976546 | 지상 10층 | 지상 10층 | 2976482 | 741 | 0.19525 | 0.00741 | 0.3805
2976547 | 지상 10층 | 지상 10층 | 2976482 | 741 | 0.19525 | 0.00741 | 0.3805
2976548 | 지상 10층 | 지상 10층 | 2976482 | 716 | 0.189 | 0.00716 | 0.378
2976549 | 지상 10층 | 지상 10층 | 2976482 | 716 | 0.189 | 0.00716 | 0.378
2976550 | 지상 10층 | 지상 10층 | 2976482 | 300 | 0.085 | 0.003 | 0.16
2976551 | 지상 10층 | 지상 10층 | 2976482 | 600 | 0.16 | 0.006 | 0.3
2976552 | 지상 10층 | 지상 10층 | 2976482 | 2100 | 0.535 | 0.021 | 1.06
2976557 | 지상 10층 | 지상 10층 | 2976482 | 741 | 0.19525 | 0.00741 | 0.3805
2976558 | 지상 10층 | 지상 10층 | 2976482 | 741 | 0.19525 | 0.00741 | 0.3805
2976559 | 지상 10층 | 지상 10층 | 2976482 | 716 | 0.189 | 0.00716 | 0.378
2976560 | 지상 10층 | 지상 10층 | 2976482 | 716 | 0.189 | 0.00716 | 0.378
2976561 | 지상 10층 | 지상 10층 | 2976482 | 300 | 0.085 | 0.003 | 0.16
2976562 | 지상 10층 | 지상 10층 | 2976482 | 600 | 0.16 | 0.006 | 0.3
2976563 | 지상 10층 | 지상 10층 | 2976482 | 2100 | 0.535 | 0.021 | 1.06
2976568 | 지상 10층 | 지상 10층 | 2976482 | 741 | 0.19525 | 0.00741 | 0.3805
2976569 | 지상 10층 | 지상 10층 | 2976482 | 741 | 0.19525 | 0.00741 | 0.3805
2976570 | 지상 10층 | 지상 10층 | 2976482 | 716 | 0.189 | 0.00716 | 0.378
2976571 | 지상 10층 | 지상 10층 | 2976482 | 716 | 0.189 | 0.00716 | 0.378
2976572 | 지상 10층 | 지상 10층 | 2976482 | 300 | 0.085 | 0.003 | 0.16
2976573 | 지상 10층 | 지상 10층 | 2976482 | 600 | 0.16 | 0.006 | 0.3
2976574 | 지상 10층 | 지상 10층 | 2976482 | 2100 | 0.535 | 0.021 | 1.06
2976579 | 지상 10층 | 지상 10층 | 2976482 | 1000 | 0.26 | 0.01 | 0.52
2976580 | 지상 10층 | 지상 10층 | 2976482 | 801 | 0.21025 | 0.00801 | 0.4105
2976581 | 지상 10층 | 지상 10층 | 2976482 | 776 | 0.204 | 0.00776 | 0.408
2976582 | 지상 10층 | 지상 10층 | 2976482 | 776 | 0.204 | 0.00776 | 0.408
2976583 | 지상 10층 | 지상 10층 | 2976482 | 300 | 0.085 | 0.003 | 0.16
2976584 | 지상 10층 | 지상 10층 | 2976482 | 600 | 0.16 | 0.006 | 0.3
2976585 | 지상 10층 | 지상 10층 | 2976482 | 2100 | 0.535 | 0.021 | 1.06
2976590 | 지상 10층 | 지상 10층 | 2976482 | 801 | 0.21025 | 0.00801 | 0.4105
2976591 | 지상 10층 | 지상 10층 | 2976482 | 1000 | 0.26 | 0.01 | 0.52
2976592 | 지상 10층 | 지상 10층 | 2976482 | 1000 | 0.26 | 0.01 | 0.52
2976593 | 지상 10층 | 지상 10층 | 2976482 | 1000 | 0.26 | 0.01 | 0.52
2976594 | 지상 10층 | 지상 10층 | 2976482 | 300 | 0.085 | 0.003 | 0.16
2976595 | 지상 10층 | 지상 10층 | 2976482 | 600 | 0.16 | 0.006 | 0.3
2976596 | 지상 10층 | 지상 10층 | 2976482 | 2100 | 0.535 | 0.021 | 1.06
2976601 | 지상 10층 | 지상 10층 | 2976482 | 741 | 0.19525 | 0.00741 | 0.3805
2976602 | 지상 10층 | 지상 10층 | 2976482 | 741 | 0.19525 | 0.00741 | 0.3805
2976603 | 지상 10층 | 지상 10층 | 2976482 | 716 | 0.189 | 0.00716 | 0.378
2976604 | 지상 10층 | 지상 10층 | 2976482 | 716 | 0.189 | 0.00716 | 0.378
2976605 | 지상 10층 | 지상 10층 | 2976482 | 300 | 0.085 | 0.003 | 0.16
2976606 | 지상 10층 | 지상 10층 | 2976482 | 600 | 0.16 | 0.006 | 0.3
2976607 | 지상 10층 | 지상 10층 | 2976482 | 2100 | 0.535 | 0.021 | 1.06
2976612 | 지상 10층 | 지상 10층 | 2976482 | 741 | 0.19525 | 0.00741 | 0.3805
2976613 | 지상 10층 | 지상 10층 | 2976482 | 741 | 0.19525 | 0.00741 | 0.3805
2976614 | 지상 10층 | 지상 10층 | 2976482 | 716 | 0.189 | 0.00716 | 0.378
2976615 | 지상 10층 | 지상 10층 | 2976482 | 716 | 0.189 | 0.00716 | 0.378
2976616 | 지상 10층 | 지상 10층 | 2976482 | 300 | 0.085 | 0.003 | 0.16
2976617 | 지상 10층 | 지상 10층 | 2976482 | 600 | 0.16 | 0.006 | 0.3
2976618 | 지상 10층 | 지상 10층 | 2976482 | 2100 | 0.535 | 0.021 | 1.06
2976623 | 지상 10층 | 지상 10층 | 2976482 | 741 | 0.19525 | 0.00741 | 0.3805
2976624 | 지상 10층 | 지상 10층 | 2976482 | 741 | 0.19525 | 0.00741 | 0.3805
2976625 | 지상 10층 | 지상 10층 | 2976482 | 716 | 0.189 | 0.00716 | 0.378
2976626 | 지상 10층 | 지상 10층 | 2976482 | 716 | 0.189 | 0.00716 | 0.378
2976627 | 지상 10층 | 지상 10층 | 2976482 | 300 | 0.085 | 0.003 | 0.16
2976628 | 지상 10층 | 지상 10층 | 2976482 | 600 | 0.16 | 0.006 | 0.3
2976629 | 지상 10층 | 지상 10층 | 2976482 | 2100 | 0.535 | 0.021 | 1.06
2976634 | 지상 10층 | 지상 10층 | 2976482 | 1000 | 0.26 | 0.01 | 0.52
2976635 | 지상 10층 | 지상 10층 | 2976482 | 801 | 0.21025 | 0.00801 | 0.4105
2976636 | 지상 10층 | 지상 10층 | 2976482 | 776 | 0.204 | 0.00776 | 0.408
2976637 | 지상 10층 | 지상 10층 | 2976482 | 776 | 0.204 | 0.00776 | 0.408
2976638 | 지상 10층 | 지상 10층 | 2976482 | 300 | 0.085 | 0.003 | 0.16
2976639 | 지상 10층 | 지상 10층 | 2976482 | 600 | 0.16 | 0.006 | 0.3
2976640 | 지상 10층 | 지상 10층 | 2976482 | 2100 | 0.535 | 0.021 | 1.06
2976645 | 지상 10층 | 지상 10층 | 2976482 | 814 | 0.2135 | 0.00814 | 0.417
2976646 | 지상 10층 | 지상 10층 | 2976482 | 1000 | 0.26 | 0.01 | 0.52
2976647 | 지상 10층 | 지상 10층 | 2976482 | 1000 | 0.26 | 0.01 | 0.52
2976648 | 지상 10층 | 지상 10층 | 2976482 | 1000 | 0.26 | 0.01 | 0.52
2976649 | 지상 10층 | 지상 10층 | 2976482 | 300 | 0.085 | 0.003 | 0.16
2976650 | 지상 10층 | 지상 10층 | 2976482 | 600 | 0.16 | 0.006 | 0.3
2976651 | 지상 10층 | 지상 10층 | 2976482 | 2100 | 0.535 | 0.021 | 1.06
2976656 | 지상 10층 | 지상 10층 | 2976482 | 754 | 0.1985 | 0.00754 | 0.387
2976657 | 지상 10층 | 지상 10층 | 2976482 | 754 | 0.1985 | 0.00754 | 0.387
2976658 | 지상 10층 | 지상 10층 | 2976482 | 729 | 0.19225 | 0.00729 | 0.3845
2976659 | 지상 10층 | 지상 10층 | 2976482 | 729 | 0.19225 | 0.00729 | 0.3845
2976660 | 지상 10층 | 지상 10층 | 2976482 | 300 | 0.085 | 0.003 | 0.16
2976661 | 지상 10층 | 지상 10층 | 2976482 | 600 | 0.16 | 0.006 | 0.3
2976662 | 지상 10층 | 지상 10층 | 2976482 | 2100 | 0.535 | 0.021 | 1.06
2976667 | 지상 10층 | 지상 10층 | 2976482 | 754 | 0.1985 | 0.00754 | 0.387
2976668 | 지상 10층 | 지상 10층 | 2976482 | 754 | 0.1985 | 0.00754 | 0.387
2976669 | 지상 10층 | 지상 10층 | 2976482 | 729 | 0.19225 | 0.00729 | 0.3845
2976670 | 지상 10층 | 지상 10층 | 2976482 | 729 | 0.19225 | 0.00729 | 0.3845
2976671 | 지상 10층 | 지상 10층 | 2976482 | 300 | 0.085 | 0.003 | 0.16
2976672 | 지상 10층 | 지상 10층 | 2976482 | 600 | 0.16 | 0.006 | 0.3
2976673 | 지상 10층 | 지상 10층 | 2976482 | 2100 | 0.535 | 0.021 | 1.06
2976678 | 지상 10층 | 지상 10층 | 2976482 | 754 | 0.1985 | 0.00754 | 0.387
2976679 | 지상 10층 | 지상 10층 | 2976482 | 754 | 0.1985 | 0.00754 | 0.387
2976680 | 지상 10층 | 지상 10층 | 2976482 | 729 | 0.19225 | 0.00729 | 0.3845
2976681 | 지상 10층 | 지상 10층 | 2976482 | 729 | 0.19225 | 0.00729 | 0.3845
2976682 | 지상 10층 | 지상 10층 | 2976482 | 300 | 0.085 | 0.003 | 0.16
2976683 | 지상 10층 | 지상 10층 | 2976482 | 600 | 0.16 | 0.006 | 0.3
2976684 | 지상 10층 | 지상 10층 | 2976482 | 2100 | 0.535 | 0.021 | 1.06
2976689 | 지상 10층 | 지상 10층 | 2976482 | 725 | 0.19125 | 0.00725 | 0.3725
2976690 | 지상 10층 | 지상 10층 | 2976482 | 754 | 0.1985 | 0.00754 | 0.387
2976691 | 지상 10층 | 지상 10층 | 2976482 | 729 | 0.19225 | 0.00729 | 0.3845
2976692 | 지상 10층 | 지상 10층 | 2976482 | 729 | 0.19225 | 0.00729 | 0.3845
2976693 | 지상 10층 | 지상 10층 | 2976482 | 300 | 0.085 | 0.003 | 0.16
2976694 | 지상 10층 | 지상 10층 | 2976482 | 600 | 0.16 | 0.006 | 0.3
2976695 | 지상 10층 | 지상 10층 | 2976482 | 2100 | 0.535 | 0.021 | 1.06
2976700 | 지상 10층 | 지상 10층 | 2976482 | 667 | 0.17675 | 0.00667 | 0.3435
2976701 | 지상 10층 | 지상 10층 | 2976482 | 727 | 0.19175 | 0.00727 | 0.3735
2976702 | 지상 10층 | 지상 10층 | 2976482 | 702 | 0.1855 | 0.00702 | 0.371
2976703 | 지상 10층 | 지상 10층 | 2976482 | 702 | 0.1855 | 0.00702 | 0.371
2976704 | 지상 10층 | 지상 10층 | 2976482 | 650 | 0.1725 | 0.0065 | 0.345
2976709 | 지상 10층 | 지상 10층 | 2976482 | 741 | 0.19525 | 0.00741 | 0.3805
2976710 | 지상 10층 | 지상 10층 | 2976482 | 741 | 0.19525 | 0.00741 | 0.3805
2976711 | 지상 10층 | 지상 10층 | 2976482 | 716 | 0.189 | 0.00716 | 0.378
2976712 | 지상 10층 | 지상 10층 | 2976482 | 716 | 0.189 | 0.00716 | 0.378
2976713 | 지상 10층 | 지상 10층 | 2976482 | 650 | 0.1725 | 0.0065 | 0.345
2976718 | 지상 10층 | 지상 10층 | 2976482 | 741 | 0.19525 | 0.00741 | 0.3805
2976719 | 지상 10층 | 지상 10층 | 2976482 | 741 | 0.19525 | 0.00741 | 0.3805
2976720 | 지상 10층 | 지상 10층 | 2976482 | 716 | 0.189 | 0.00716 | 0.378
2976721 | 지상 10층 | 지상 10층 | 2976482 | 716 | 0.189 | 0.00716 | 0.378
2976722 | 지상 10층 | 지상 10층 | 2976482 | 650 | 0.1725 | 0.0065 | 0.345
2976727 | 지상 10층 | 지상 10층 | 2976482 | 741 | 0.19525 | 0.00741 | 0.3805
2976728 | 지상 10층 | 지상 10층 | 2976482 | 741 | 0.19525 | 0.00741 | 0.3805
2976729 | 지상 10층 | 지상 10층 | 2976482 | 716 | 0.189 | 0.00716 | 0.378
2976730 | 지상 10층 | 지상 10층 | 2976482 | 716 | 0.189 | 0.00716 | 0.378
2976731 | 지상 10층 | 지상 10층 | 2976482 | 650 | 0.1725 | 0.0065 | 0.345
2976736 | 지상 10층 | 지상 10층 | 2976482 | 741 | 0.19525 | 0.00741 | 0.3805
2976737 | 지상 10층 | 지상 10층 | 2976482 | 741 | 0.19525 | 0.00741 | 0.3805
2976738 | 지상 10층 | 지상 10층 | 2976482 | 716 | 0.189 | 0.00716 | 0.378
2976739 | 지상 10층 | 지상 10층 | 2976482 | 716 | 0.189 | 0.00716 | 0.378
2976740 | 지상 10층 | 지상 10층 | 2976482 | 650 | 0.1725 | 0.0065 | 0.345
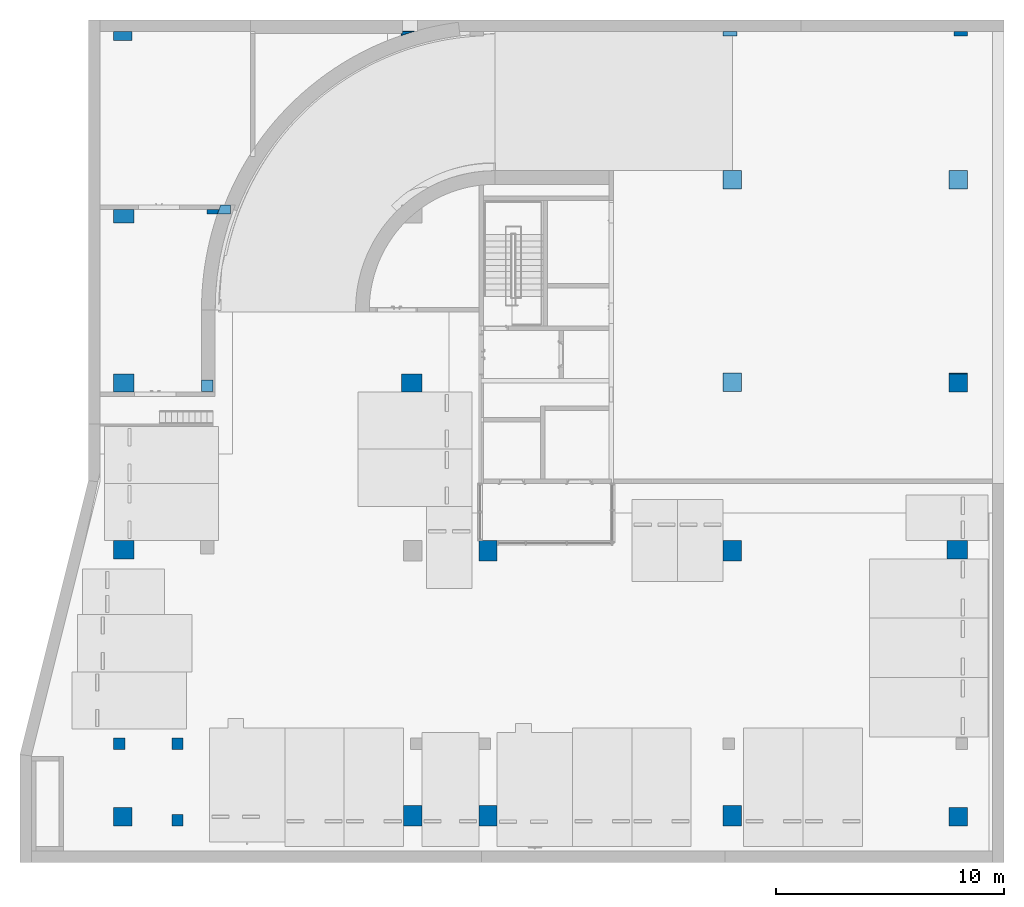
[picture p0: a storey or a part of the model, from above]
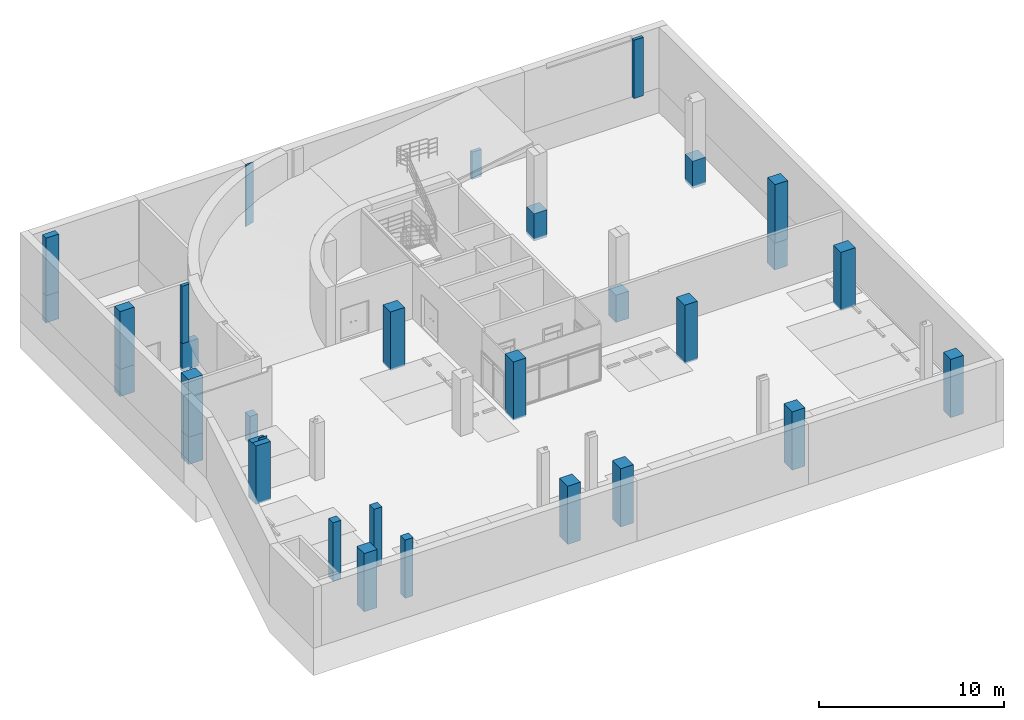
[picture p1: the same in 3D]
Properties of the parts of a building model (IFC2X3), part 20 of 39

# IfcMember: 직사각형 멀리언:CW200-직사각형 멀리언 50x200mm (8700)
Name (직사각형 멀리언:CW200-직사각형 멀리언 50x200mm:...) | In | 레벨 | 호스트 ID | 길이 (mm) = Span (mm) | 면적 (m2) = CrossSectionArea (m2) | 체적 (m3) = NetVolume (m3) | NetSurfaceArea (m2)
2976745 | 지상 10층 | 지상 10층 | 2976482 | 741 | 0.19525 | 0.00741 | 0.3805
2976746 | 지상 10층 | 지상 10층 | 2976482 | 741 | 0.19525 | 0.00741 | 0.3805
2976747 | 지상 10층 | 지상 10층 | 2976482 | 716 | 0.189 | 0.00716 | 0.378
2976748 | 지상 10층 | 지상 10층 | 2976482 | 716 | 0.189 | 0.00716 | 0.378
2976749 | 지상 10층 | 지상 10층 | 2976482 | 650 | 0.1725 | 0.0065 | 0.345
2976754 | 지상 10층 | 지상 10층 | 2976482 | 801 | 0.21025 | 0.00801 | 0.4105
2976755 | 지상 10층 | 지상 10층 | 2976482 | 741 | 0.19525 | 0.00741 | 0.3805
2976756 | 지상 10층 | 지상 10층 | 2976482 | 716 | 0.189 | 0.00716 | 0.378
2976757 | 지상 10층 | 지상 10층 | 2976482 | 716 | 0.189 | 0.00716 | 0.378
2976758 | 지상 10층 | 지상 10층 | 2976482 | 650 | 0.1725 | 0.0065 | 0.345
2976763 | 지상 10층 | 지상 10층 | 2976482 | 741 | 0.19525 | 0.00741 | 0.3805
2976764 | 지상 10층 | 지상 10층 | 2976482 | 801 | 0.21025 | 0.00801 | 0.4105
2976765 | 지상 10층 | 지상 10층 | 2976482 | 776 | 0.204 | 0.00776 | 0.408
2976766 | 지상 10층 | 지상 10층 | 2976482 | 776 | 0.204 | 0.00776 | 0.408
2976767 | 지상 10층 | 지상 10층 | 2976482 | 650 | 0.1725 | 0.0065 | 0.345
2976772 | 지상 10층 | 지상 10층 | 2976482 | 741 | 0.19525 | 0.00741 | 0.3805
2976773 | 지상 10층 | 지상 10층 | 2976482 | 741 | 0.19525 | 0.00741 | 0.3805
2976774 | 지상 10층 | 지상 10층 | 2976482 | 716 | 0.189 | 0.00716 | 0.378
2976775 | 지상 10층 | 지상 10층 | 2976482 | 716 | 0.189 | 0.00716 | 0.378
2976776 | 지상 10층 | 지상 10층 | 2976482 | 650 | 0.1725 | 0.0065 | 0.345
2976781 | 지상 10층 | 지상 10층 | 2976482 | 741 | 0.19525 | 0.00741 | 0.3805
2976782 | 지상 10층 | 지상 10층 | 2976482 | 741 | 0.19525 | 0.00741 | 0.3805
2976783 | 지상 10층 | 지상 10층 | 2976482 | 716 | 0.189 | 0.00716 | 0.378
2976784 | 지상 10층 | 지상 10층 | 2976482 | 716 | 0.189 | 0.00716 | 0.378
2976785 | 지상 10층 | 지상 10층 | 2976482 | 650 | 0.1725 | 0.0065 | 0.345
2976790 | 지상 10층 | 지상 10층 | 2976482 | 801 | 0.21025 | 0.00801 | 0.4105
2976791 | 지상 10층 | 지상 10층 | 2976482 | 741 | 0.19525 | 0.00741 | 0.3805
2976792 | 지상 10층 | 지상 10층 | 2976482 | 716 | 0.189 | 0.00716 | 0.378
2976793 | 지상 10층 | 지상 10층 | 2976482 | 716 | 0.189 | 0.00716 | 0.378
2976794 | 지상 10층 | 지상 10층 | 2976482 | 650 | 0.1725 | 0.0065 | 0.345
2976799 | 지상 10층 | 지상 10층 | 2976482 | 754 | 0.1985 | 0.00754 | 0.387
2976800 | 지상 10층 | 지상 10층 | 2976482 | 814 | 0.2135 | 0.00814 | 0.417
2976801 | 지상 10층 | 지상 10층 | 2976482 | 789 | 0.20725 | 0.00789 | 0.4145
2976802 | 지상 10층 | 지상 10층 | 2976482 | 789 | 0.20725 | 0.00789 | 0.4145
2976803 | 지상 10층 | 지상 10층 | 2976482 | 650 | 0.1725 | 0.0065 | 0.345
2976808 | 지상 10층 | 지상 10층 | 2976482 | 754 | 0.1985 | 0.00754 | 0.387
2976809 | 지상 10층 | 지상 10층 | 2976482 | 754 | 0.1985 | 0.00754 | 0.387
2976810 | 지상 10층 | 지상 10층 | 2976482 | 729 | 0.19225 | 0.00729 | 0.3845
2976811 | 지상 10층 | 지상 10층 | 2976482 | 729 | 0.19225 | 0.00729 | 0.3845
2976812 | 지상 10층 | 지상 10층 | 2976482 | 650 | 0.1725 | 0.0065 | 0.345
2976817 | 지상 10층 | 지상 10층 | 2976482 | 754 | 0.1985 | 0.00754 | 0.387
2976818 | 지상 10층 | 지상 10층 | 2976482 | 754 | 0.1985 | 0.00754 | 0.387
2976819 | 지상 10층 | 지상 10층 | 2976482 | 729 | 0.19225 | 0.00729 | 0.3845
2976820 | 지상 10층 | 지상 10층 | 2976482 | 729 | 0.19225 | 0.00729 | 0.3845
2976821 | 지상 10층 | 지상 10층 | 2976482 | 650 | 0.1725 | 0.0065 | 0.345
2976826 | 지상 10층 | 지상 10층 | 2976482 | 754 | 0.1985 | 0.00754 | 0.387
2976827 | 지상 10층 | 지상 10층 | 2976482 | 754 | 0.1985 | 0.00754 | 0.387
2976828 | 지상 10층 | 지상 10층 | 2976482 | 729 | 0.19225 | 0.00729 | 0.3845
2976829 | 지상 10층 | 지상 10층 | 2976482 | 729 | 0.19225 | 0.00729 | 0.3845
2976830 | 지상 10층 | 지상 10층 | 2976482 | 650 | 0.1725 | 0.0065 | 0.345
2976835 | 지상 10층 | 지상 10층 | 2976482 | 725 | 0.19125 | 0.00725 | 0.3725
2976836 | 지상 10층 | 지상 10층 | 2976482 | 700 | 0.185 | 0.007 | 0.37
2976837 | 지상 10층 | 지상 10층 | 2976482 | 700 | 0.185 | 0.007 | 0.37
2976838 | 지상 10층 | 지상 10층 | 2976482 | 926.395 | 0.241599 | 0.00926395 | 0.473197
2976839 | 지상 10층 | 지상 10층 | 2976482 | 650 | 0.1725 | 0.0065 | 0.345
3050436 | 지하2층 | 지하2층 | 3050431 | 1176.95 | 0.304239 | 0.0117695 | 0.608477
3050437 | 지하2층 | 지하2층 | 3050431 | 1173.05 | 0.303261 | 0.0117305 | 0.606523
3050438 | 지하2층 | 지하2층 | 3050431 | 2100 | 0.535 | 0.021 | 1.06
3050439 | 지하2층 | 지하2층 | 3050431 | 290 | 0.0825 | 0.0029 | 0.155
3051801 | 지하2층 | 지하2층 | 3050431 | 1173.05 | 0.303261 | 0.0117305 | 0.606523
3051802 | 지하2층 | 지하2층 | 3050431 | 1176.95 | 0.304239 | 0.0117695 | 0.608477
3051803 | 지하2층 | 지하2층 | 3050431 | 2100 | 0.535 | 0.021 | 1.06
3051992 | 지하2층 | 지하2층 | 3050431 | 290 | 0.0825 | 0.0029 | 0.155
3051993 | 지하2층 | 지하2층 | 3050431 | 2100 | 0.535 | 0.021 | 1.06
3051994 | 지하2층 | 지하2층 | 3050431 | 1173.05 | 0.303261 | 0.0117305 | 0.606523
3051995 | 지하2층 | 지하2층 | 3050431 | 1176.95 | 0.304239 | 0.0117695 | 0.608477
3051996 | 지하2층 | 지하2층 | 3050431 | 290 | 0.0825 | 0.0029 | 0.155
3050669 | 지하2층 | 지하2층 | 3050663 | 1930 | 0.4925 | 0.0193 | 0.985
3050670 | 지하2층 | 지하2층 | 3050663 | 1175 | 0.30375 | 0.01175 | 0.6075
3050671 | 지하2층 | 지하2층 | 3050663 | 2100 | 0.535 | 0.021 | 1.06
3050672 | 지하2층 | 지하2층 | 3050663 | 290 | 0.0825 | 0.0029 | 0.155
3052287 | 지하2층 | 지하2층 | 3050663 | 290 | 0.0825 | 0.0029 | 0.155
3052288 | 지하2층 | 지하2층 | 3050663 | 2100 | 0.535 | 0.021 | 1.06
3052289 | 지하2층 | 지하2층 | 3050663 | 1175 | 0.30375 | 0.01175 | 0.6075
3052459 | 지하2층 | 지하2층 | 3050663 | 1175 | 0.30375 | 0.01175 | 0.6075
3052460 | 지하2층 | 지하2층 | 3050663 | 1750 | 0.4475 | 0.0175 | 0.895
3052461 | 지하2층 | 지하2층 | 3050663 | 1750 | 0.4475 | 0.0175 | 0.895
3052462 | 지하2층 | 지하2층 | 3050663 | 2100 | 0.535 | 0.021 | 1.06
3052463 | 지하2층 | 지하2층 | 3050663 | 290 | 0.0825 | 0.0029 | 0.155
3052544 | 지하2층 | 지하2층 | 3050663 | 1750 | 0.4475 | 0.0175 | 0.895
3052545 | 지하2층 | 지하2층 | 3050663 | 1930 | 0.4925 | 0.0193 | 0.985
3052546 | 지하2층 | 지하2층 | 3050663 | 1930 | 0.4925 | 0.0193 | 0.985
3052547 | 지하2층 | 지하2층 | 3050663 | 2100 | 0.535 | 0.021 | 1.06
3052548 | 지하2층 | 지하2층 | 3050663 | 290 | 0.0825 | 0.0029 | 0.155
3050967 | 지하2층 | 지하2층 | 3050962 | 1358.32 | 0.349579 | 0.0135832 | 0.699158
3050968 | 지하2층 | 지하2층 | 3050962 | 1091.68 | 0.282921 | 0.0109168 | 0.565842
3050969 | 지하2층 | 지하2층 | 3050962 | 2100 | 0.535 | 0.021 | 1.06
3050970 | 지하2층 | 지하2층 | 3050962 | 290 | 0.0825 | 0.0029 | 0.155
3053274 | 지하2층 | 지하2층 | 3050962 | 290 | 0.0825 | 0.0029 | 0.155
3053275 | 지하2층 | 지하2층 | 3050962 | 2100 | 0.535 | 0.021 | 1.06
3053276 | 지하2층 | 지하2층 | 3050962 | 1091.68 | 0.282921 | 0.0109168 | 0.565842
3053500 | 지하2층 | 지하2층 | 3050962 | 1091.68 | 0.282921 | 0.0109168 | 0.565842
3053501 | 지하2층 | 지하2층 | 3050962 | 1358.32 | 0.349579 | 0.0135832 | 0.699158
3053502 | 지하2층 | 지하2층 | 3050962 | 1358.32 | 0.349579 | 0.0135832 | 0.699158
3053503 | 지하2층 | 지하2층 | 3050962 | 2100 | 0.535 | 0.021 | 1.06
3053504 | 지하2층 | 지하2층 | 3050962 | 290 | 0.0825 | 0.0029 | 0.155
3054005 | 지하1층 | 지하1층 | 3054003 | 1173.05 | 0.303261 | 0.0117305 | 0.606523
3054006 | 지하1층 | 지하1층 | 3054003 | 1173.05 | 0.303261 | 0.0117305 | 0.606523
3054007 | 지하1층 | 지하1층 | 3054003 | 2100 | 0.535 | 0.021 | 1.06
3054008 | 지하1층 | 지하1층 | 3054003 | 500 | 0.135 | 0.005 | 0.26
3054023 | 지하1층 | 지하1층 | 3054003 | 1173.05 | 0.303261 | 0.0117305 | 0.606523
3054024 | 지하1층 | 지하1층 | 3054003 | 1173.05 | 0.303261 | 0.0117305 | 0.606523
3054025 | 지하1층 | 지하1층 | 3054003 | 2100 | 0.535 | 0.021 | 1.06
3054029 | 지하1층 | 지하1층 | 3054003 | 500 | 0.135 | 0.005 | 0.26
3054030 | 지하1층 | 지하1층 | 3054003 | 2100 | 0.535 | 0.021 | 1.06
3054031 | 지하1층 | 지하1층 | 3054003 | 1173.05 | 0.303261 | 0.0117305 | 0.606523
3054032 | 지하1층 | 지하1층 | 3054003 | 1173.05 | 0.303261 | 0.0117305 | 0.606523
3054033 | 지하1층 | 지하1층 | 3054003 | 500 | 0.135 | 0.005 | 0.26
3054011 | 지하1층 | 지하1층 | 3054009 | 1925 | 0.49125 | 0.01925 | 0.9825
3054012 | 지하1층 | 지하1층 | 3054009 | 1175 | 0.30375 | 0.01175 | 0.6075
3054013 | 지하1층 | 지하1층 | 3054009 | 2100 | 0.535 | 0.021 | 1.06
3054014 | 지하1층 | 지하1층 | 3054009 | 500 | 0.135 | 0.005 | 0.26
3054036 | 지하1층 | 지하1층 | 3054009 | 500 | 0.135 | 0.005 | 0.26
3054037 | 지하1층 | 지하1층 | 3054009 | 2100 | 0.535 | 0.021 | 1.06
3054038 | 지하1층 | 지하1층 | 3054009 | 1175 | 0.30375 | 0.01175 | 0.6075
3054042 | 지하1층 | 지하1층 | 3054009 | 1175 | 0.30375 | 0.01175 | 0.6075
3054043 | 지하1층 | 지하1층 | 3054009 | 1750 | 0.4475 | 0.0175 | 0.895
3054044 | 지하1층 | 지하1층 | 3054009 | 1750 | 0.4475 | 0.0175 | 0.895
3054045 | 지하1층 | 지하1층 | 3054009 | 2100 | 0.535 | 0.021 | 1.06
3054046 | 지하1층 | 지하1층 | 3054009 | 500 | 0.135 | 0.005 | 0.26
3054050 | 지하1층 | 지하1층 | 3054009 | 1750 | 0.4475 | 0.0175 | 0.895
3054051 | 지하1층 | 지하1층 | 3054009 | 1925 | 0.49125 | 0.01925 | 0.9825
3054052 | 지하1층 | 지하1층 | 3054009 | 1925 | 0.49125 | 0.01925 | 0.9825
3054053 | 지하1층 | 지하1층 | 3054009 | 2100 | 0.535 | 0.021 | 1.06
3054054 | 지하1층 | 지하1층 | 3054009 | 500 | 0.135 | 0.005 | 0.26
3054017 | 지하1층 | 지하1층 | 3054015 | 1354.41 | 0.348601 | 0.0135441 | 0.697203
3054018 | 지하1층 | 지하1층 | 3054015 | 1091.68 | 0.282921 | 0.0109168 | 0.565842
3054019 | 지하1층 | 지하1층 | 3054015 | 2100 | 0.535 | 0.021 | 1.06
3054020 | 지하1층 | 지하1층 | 3054015 | 500 | 0.135 | 0.005 | 0.26
3054057 | 지하1층 | 지하1층 | 3054015 | 500 | 0.135 | 0.005 | 0.26
3054058 | 지하1층 | 지하1층 | 3054015 | 2100 | 0.535 | 0.021 | 1.06
3054059 | 지하1층 | 지하1층 | 3054015 | 1091.68 | 0.282921 | 0.0109168 | 0.565842
3054063 | 지하1층 | 지하1층 | 3054015 | 1091.68 | 0.282921 | 0.0109168 | 0.565842
3054064 | 지하1층 | 지하1층 | 3054015 | 1354.41 | 0.348601 | 0.0135441 | 0.697203
3054065 | 지하1층 | 지하1층 | 3054015 | 1354.41 | 0.348601 | 0.0135441 | 0.697203
3054066 | 지하1층 | 지하1층 | 3054015 | 2100 | 0.535 | 0.021 | 1.06
3054067 | 지하1층 | 지하1층 | 3054015 | 500 | 0.135 | 0.005 | 0.26
3118407 | 지상 1층 | 지상 1층 | 3118405 | 345.118 | 0.0962794 | 0.00345118 | 0.182559
3118408 | 지상 1층 | 지상 1층 | 3118405 | 275 | 0.07875 | 0.00275 | 0.1575
3118409 | 지상 1층 | 지상 1층 | 3118405 | 2100 | 0.535 | 0.021 | 1.06
3118410 | 지상 1층 | 지상 1층 | 3118405 | 1420 | 0.365 | 0.0142 | 0.72
3118413 | 지상 1층 | 지상 1층 | 3118405 | 1800 | 0.46 | 0.018 | 0.9
3118414 | 지상 1층 | 지상 1층 | 3118405 | 320.118 | 0.0900294 | 0.00320118 | 0.180059
3118415 | 지상 1층 | 지상 1층 | 3118405 | 2125 | 0.54125 | 0.02125 | 1.0825
3118418 | 지상 1층 | 지상 1층 | 3118405 | 300 | 0.085 | 0.003 | 0.16
3118420 | 지상 1층 | 지상 1층 | 3118405 | 2125 | 0.54125 | 0.02125 | 1.0825
3118425 | 지상 1층 | 지상 1층 | 3118405 | 1420 | 0.365 | 0.0142 | 0.72
3118426 | 지상 1층 | 지상 1층 | 3118405 | 2100 | 0.535 | 0.021 | 1.06
3118427 | 지상 1층 | 지상 1층 | 3118405 | 275 | 0.07875 | 0.00275 | 0.1575
3118428 | 지상 1층 | 지상 1층 | 3118405 | 1750 | 0.4475 | 0.0175 | 0.895
3118429 | 지상 1층 | 지상 1층 | 3118405 | 320.118 | 0.0900294 | 0.00320118 | 0.180059
3181687 | 지상 2층 | 지상 2층 | 3181685 | 225.009 | 0.0662522 | 0.00225009 | 0.132504
3181689 | 지상 2층 | 지상 2층 | 3181685 | 1050 | 0.2725 | 0.0105 | 0.535
3181690 | 지상 2층 | 지상 2층 | 3181685 | 970 | 0.2525 | 0.0097 | 0.495
3181693 | 지상 2층 | 지상 2층 | 3181685 | 925 | 0.24125 | 0.00925 | 0.4825
3181694 | 지상 2층 | 지상 2층 | 3181685 | 225.009 | 0.0662522 | 0.00225009 | 0.132504
3181695 | 지상 2층 | 지상 2층 | 3181685 | 1050 | 0.2725 | 0.0105 | 0.535
3181699 | 지상 2층 | 지상 2층 | 3181685 | 970 | 0.2525 | 0.0097 | 0.495
3181700 | 지상 2층 | 지상 2층 | 3181685 | 1050 | 0.2725 | 0.0105 | 0.535
3181701 | 지상 2층 | 지상 2층 | 3181685 | 225.009 | 0.0662522 | 0.00225009 | 0.132504
3181702 | 지상 2층 | 지상 2층 | 3181685 | 970 | 0.2525 | 0.0097 | 0.495
3181712 | 지상 3층 | 지상 3층 | 3181710 | 175 | 0.05375 | 0.00175 | 0.1075
3181714 | 지상 3층 | 지상 3층 | 3181710 | 1050 | 0.2725 | 0.0105 | 0.535
3181715 | 지상 3층 | 지상 3층 | 3181710 | 970 | 0.2525 | 0.0097 | 0.495
3181718 | 지상 3층 | 지상 3층 | 3181710 | 925 | 0.24125 | 0.00925 | 0.4825
3181719 | 지상 3층 | 지상 3층 | 3181710 | 175 | 0.05375 | 0.00175 | 0.1075
3181720 | 지상 3층 | 지상 3층 | 3181710 | 1050 | 0.2725 | 0.0105 | 0.535
3181724 | 지상 3층 | 지상 3층 | 3181710 | 970 | 0.2525 | 0.0097 | 0.495
3181725 | 지상 3층 | 지상 3층 | 3181710 | 1050 | 0.2725 | 0.0105 | 0.535
3181726 | 지상 3층 | 지상 3층 | 3181710 | 175 | 0.05375 | 0.00175 | 0.1075
3181727 | 지상 3층 | 지상 3층 | 3181710 | 970 | 0.2525 | 0.0097 | 0.495
3181733 | 지상 4층 | 지상 4층 | 3181731 | 175 | 0.05375 | 0.00175 | 0.1075
3181735 | 지상 4층 | 지상 4층 | 3181731 | 1050 | 0.2725 | 0.0105 | 0.535
3181736 | 지상 4층 | 지상 4층 | 3181731 | 970 | 0.2525 | 0.0097 | 0.495
3181739 | 지상 4층 | 지상 4층 | 3181731 | 925 | 0.24125 | 0.00925 | 0.4825
3181741 | 지상 4층 | 지상 4층 | 3181731 | 1050 | 0.2725 | 0.0105 | 0.535
3181745 | 지상 4층 | 지상 4층 | 3181731 | 970 | 0.2525 | 0.0097 | 0.495
3181746 | 지상 4층 | 지상 4층 | 3181731 | 1050 | 0.2725 | 0.0105 | 0.535
3181747 | 지상 4층 | 지상 4층 | 3181731 | 175 | 0.05375 | 0.00175 | 0.1075
3181748 | 지상 4층 | 지상 4층 | 3181731 | 970 | 0.2525 | 0.0097 | 0.495
3181754 | 지상 5층 | 지상 5층 | 3181752 | 225.009 | 0.0662522 | 0.00225009 | 0.132504
3181756 | 지상 5층 | 지상 5층 | 3181752 | 1050 | 0.2725 | 0.0105 | 0.535
3181757 | 지상 5층 | 지상 5층 | 3181752 | 970 | 0.2525 | 0.0097 | 0.495
3181760 | 지상 5층 | 지상 5층 | 3181752 | 925 | 0.24125 | 0.00925 | 0.4825
3181762 | 지상 5층 | 지상 5층 | 3181752 | 1050 | 0.2725 | 0.0105 | 0.535
3181766 | 지상 5층 | 지상 5층 | 3181752 | 970 | 0.2525 | 0.0097 | 0.495
3181767 | 지상 5층 | 지상 5층 | 3181752 | 1050 | 0.2725 | 0.0105 | 0.535
3181768 | 지상 5층 | 지상 5층 | 3181752 | 225.009 | 0.0662522 | 0.00225009 | 0.132504
3181769 | 지상 5층 | 지상 5층 | 3181752 | 970 | 0.2525 | 0.0097 | 0.495
3181775 | 지상 6층 | 지상 6층 | 3181773 | 225.009 | 0.0662522 | 0.00225009 | 0.132504
3181777 | 지상 6층 | 지상 6층 | 3181773 | 1050 | 0.2725 | 0.0105 | 0.535
3181778 | 지상 6층 | 지상 6층 | 3181773 | 970 | 0.2525 | 0.0097 | 0.495
3181781 | 지상 6층 | 지상 6층 | 3181773 | 925 | 0.24125 | 0.00925 | 0.4825
3181783 | 지상 6층 | 지상 6층 | 3181773 | 1050 | 0.2725 | 0.0105 | 0.535
3181787 | 지상 6층 | 지상 6층 | 3181773 | 970 | 0.2525 | 0.0097 | 0.495
3181788 | 지상 6층 | 지상 6층 | 3181773 | 1050 | 0.2725 | 0.0105 | 0.535
3181789 | 지상 6층 | 지상 6층 | 3181773 | 225.009 | 0.0662522 | 0.00225009 | 0.132504
3181790 | 지상 6층 | 지상 6층 | 3181773 | 970 | 0.2525 | 0.0097 | 0.495
3181796 | 지상 7층 | 지상 7층 | 3181794 | 225.009 | 0.0662522 | 0.00225009 | 0.132504
3181798 | 지상 7층 | 지상 7층 | 3181794 | 1050 | 0.2725 | 0.0105 | 0.535
3181799 | 지상 7층 | 지상 7층 | 3181794 | 970 | 0.2525 | 0.0097 | 0.495
3181802 | 지상 7층 | 지상 7층 | 3181794 | 925 | 0.24125 | 0.00925 | 0.4825
3181804 | 지상 7층 | 지상 7층 | 3181794 | 1050 | 0.2725 | 0.0105 | 0.535
3181808 | 지상 7층 | 지상 7층 | 3181794 | 970 | 0.2525 | 0.0097 | 0.495
3181809 | 지상 7층 | 지상 7층 | 3181794 | 1050 | 0.2725 | 0.0105 | 0.535
3181810 | 지상 7층 | 지상 7층 | 3181794 | 225.009 | 0.0662522 | 0.00225009 | 0.132504
3181811 | 지상 7층 | 지상 7층 | 3181794 | 970 | 0.2525 | 0.0097 | 0.495
3181817 | 지상 8층 | 지상 8층 | 3181815 | 225.009 | 0.0662522 | 0.00225009 | 0.132504
3181819 | 지상 8층 | 지상 8층 | 3181815 | 1050 | 0.2725 | 0.0105 | 0.535
3181820 | 지상 8층 | 지상 8층 | 3181815 | 970 | 0.2525 | 0.0097 | 0.495
3181823 | 지상 8층 | 지상 8층 | 3181815 | 925 | 0.24125 | 0.00925 | 0.4825
3181825 | 지상 8층 | 지상 8층 | 3181815 | 1050 | 0.2725 | 0.0105 | 0.535
3181829 | 지상 8층 | 지상 8층 | 3181815 | 970 | 0.2525 | 0.0097 | 0.495
3181830 | 지상 8층 | 지상 8층 | 3181815 | 1050 | 0.2725 | 0.0105 | 0.535
3181831 | 지상 8층 | 지상 8층 | 3181815 | 225.009 | 0.0662522 | 0.00225009 | 0.132504
3181832 | 지상 8층 | 지상 8층 | 3181815 | 970 | 0.2525 | 0.0097 | 0.495
3181838 | 지상 9층 | 지상 9층 | 3181836 | 225.009 | 0.0662522 | 0.00225009 | 0.132504
3181840 | 지상 9층 | 지상 9층 | 3181836 | 1050 | 0.2725 | 0.0105 | 0.535
3181841 | 지상 9층 | 지상 9층 | 3181836 | 970 | 0.2525 | 0.0097 | 0.495
3181844 | 지상 9층 | 지상 9층 | 3181836 | 925 | 0.24125 | 0.00925 | 0.4825
3181846 | 지상 9층 | 지상 9층 | 3181836 | 1050 | 0.2725 | 0.0105 | 0.535
3181850 | 지상 9층 | 지상 9층 | 3181836 | 970 | 0.2525 | 0.0097 | 0.495
3181851 | 지상 9층 | 지상 9층 | 3181836 | 1050 | 0.2725 | 0.0105 | 0.535
3181852 | 지상 9층 | 지상 9층 | 3181836 | 225.009 | 0.0662522 | 0.00225009 | 0.132504
3181853 | 지상 9층 | 지상 9층 | 3181836 | 970 | 0.2525 | 0.0097 | 0.495
3181859 | 지상 10층 | 지상 10층 | 3181857 | 485.009 | 0.131252 | 0.00485009 | 0.262504
3181861 | 지상 10층 | 지상 10층 | 3181857 | 1050 | 0.2725 | 0.0105 | 0.535
3181862 | 지상 10층 | 지상 10층 | 3181857 | 970 | 0.2525 | 0.0097 | 0.495
3181865 | 지상 10층 | 지상 10층 | 3181857 | 875 | 0.22875 | 0.00875 | 0.4575
3181867 | 지상 10층 | 지상 10층 | 3181857 | 50 | 0.0225 | 0.0005 | 0.045
3181871 | 지상 10층 | 지상 10층 | 3181857 | 970 | 0.2525 | 0.0097 | 0.495
3181872 | 지상 10층 | 지상 10층 | 3181857 | 1050 | 0.2725 | 0.0105 | 0.535
3181873 | 지상 10층 | 지상 10층 | 3181857 | 485.009 | 0.131252 | 0.00485009 | 0.262504
5355392 | 지상 4층 | 지상 4층 | 5355390 | 423.127 | 0.115782 | 0.00423127 | 0.231564
5355393 | 지상 4층 | 지상 4층 | 5355390 | 426.838 | 0.116709 | 0.00426838 | 0.233419
5355394 | 지상 4층 | 지상 4층 | 5355390 | 2100 | 0.535 | 0.021 | 1.06
5355395 | 지상 4층 | 지상 4층 | 5355390 | 520 | 0.14 | 0.0052 | 0.27
5355398 | 지상 4층 | 지상 4층 | 5355390 | 520 | 0.14 | 0.0052 | 0.27
5355399 | 지상 4층 | 지상 4층 | 5355390 | 2100 | 0.535 | 0.021 | 1.06
5355400 | 지상 4층 | 지상 4층 | 5355390 | 426.838 | 0.116709 | 0.00426838 | 0.233419
5355404 | 지상 4층 | 지상 4층 | 5355390 | 426.838 | 0.116709 | 0.00426838 | 0.233419
5355406 | 지상 4층 | 지상 4층 | 5355390 | 1450 | 0.3725 | 0.0145 | 0.745
5355407 | 지상 4층 | 지상 4층 | 5355390 | 2100 | 0.535 | 0.021 | 1.06
5355408 | 지상 4층 | 지상 4층 | 5355390 | 520 | 0.14 | 0.0052 | 0.27
5355412 | 지상 4층 | 지상 4층 | 5355390 | 1450 | 0.3725 | 0.0145 | 0.745
5355413 | 지상 4층 | 지상 4층 | 5355390 | 423.127 | 0.115782 | 0.00423127 | 0.231564
5355414 | 지상 4층 | 지상 4층 | 5355390 | 423.127 | 0.115782 | 0.00423127 | 0.231564
5355415 | 지상 4층 | 지상 4층 | 5355390 | 2100 | 0.535 | 0.021 | 1.06
5355416 | 지상 4층 | 지상 4층 | 5355390 | 520 | 0.14 | 0.0052 | 0.27
5355419 | 지상 4층 | 지상 4층 | 5355417 | 2635 | 0.66875 | 0.02635 | 1.3375
5355421 | 지상 4층 | 지상 4층 | 5355417 | 2100 | 0.535 | 0.021 | 1.06
5355422 | 지상 4층 | 지상 4층 | 5355417 | 520 | 0.14 | 0.0052 | 0.27
5355425 | 지상 4층 | 지상 4층 | 5355417 | 1500 | 0.385 | 0.015 | 0.77
5355427 | 지상 4층 | 지상 4층 | 5355417 | 2100 | 0.535 | 0.021 | 1.06
5355430 | 지상 4층 | 지상 4층 | 5355417 | 2265 | 0.57625 | 0.02265 | 1.1525
5355432 | 지상 4층 | 지상 4층 | 5355417 | 2100 | 0.535 | 0.021 | 1.06
5355437 | 지상 4층 | 지상 4층 | 5355417 | 520 | 0.14 | 0.0052 | 0.27
5355438 | 지상 4층 | 지상 4층 | 5355417 | 2100 | 0.535 | 0.021 | 1.06
5355439 | 지상 4층 | 지상 4층 | 5355417 | 2265 | 0.57625 | 0.02265 | 1.1525
5355440 | 지상 4층 | 지상 4층 | 5355417 | 1500 | 0.385 | 0.015 | 0.77
5355441 | 지상 4층 | 지상 4층 | 5355417 | 2635 | 0.66875 | 0.02635 | 1.3375
5355442 | 지상 4층 | 지상 4층 | 5355417 | 520 | 0.14 | 0.0052 | 0.27
5355443 | 지상 4층 | 지상 4층 | 5355417 | 520 | 0.14 | 0.0052 | 0.27
5355473 | 지상 4층 | 지상 4층 | 5355471 | 423.145 | 0.115786 | 0.00423145 | 0.231573
5355474 | 지상 4층 | 지상 4층 | 5355471 | 376.829 | 0.104207 | 0.00376829 | 0.208415
5355475 | 지상 4층 | 지상 4층 | 5355471 | 2100 | 0.535 | 0.021 | 1.06
5355476 | 지상 4층 | 지상 4층 | 5355471 | 520 | 0.14 | 0.0052 | 0.27
5355479 | 지상 4층 | 지상 4층 | 5355471 | 520 | 0.14 | 0.0052 | 0.27
5355480 | 지상 4층 | 지상 4층 | 5355471 | 2100 | 0.535 | 0.021 | 1.06
5355481 | 지상 4층 | 지상 4층 | 5355471 | 376.847 | 0.104212 | 0.00376847 | 0.208423
5355485 | 지상 4층 | 지상 4층 | 5355471 | 376.847 | 0.104212 | 0.00376847 | 0.208423
5355487 | 지상 4층 | 지상 4층 | 5355471 | 1500 | 0.385 | 0.015 | 0.77
5355488 | 지상 4층 | 지상 4층 | 5355471 | 2100 | 0.535 | 0.021 | 1.06
5355489 | 지상 4층 | 지상 4층 | 5355471 | 520 | 0.14 | 0.0052 | 0.27
5355493 | 지상 4층 | 지상 4층 | 5355471 | 1500 | 0.385 | 0.015 | 0.77
5355494 | 지상 4층 | 지상 4층 | 5355471 | 423.145 | 0.115786 | 0.00423145 | 0.231573
5355495 | 지상 4층 | 지상 4층 | 5355471 | 423.145 | 0.115786 | 0.00423145 | 0.231573
5355496 | 지상 4층 | 지상 4층 | 5355471 | 2100 | 0.535 | 0.021 | 1.06
5355497 | 지상 4층 | 지상 4층 | 5355471 | 520 | 0.14 | 0.0052 | 0.27
5355500 | 지상 4층 | 지상 4층 | 5355498 | 2085 | 0.53125 | 0.02085 | 1.0625
5355501 | 지상 4층 | 지상 4층 | 5355498 | 1785 | 0.45625 | 0.01785 | 0.9125
5355502 | 지상 4층 | 지상 4층 | 5355498 | 2100 | 0.535 | 0.021 | 1.06
5355503 | 지상 4층 | 지상 4층 | 5355498 | 520 | 0.14 | 0.0052 | 0.27
5355506 | 지상 4층 | 지상 4층 | 5355498 | 520 | 0.14 | 0.0052 | 0.27
5355507 | 지상 4층 | 지상 4층 | 5355498 | 2100 | 0.535 | 0.021 | 1.06
5355508 | 지상 4층 | 지상 4층 | 5355498 | 1785 | 0.45625 | 0.01785 | 0.9125
5355512 | 지상 4층 | 지상 4층 | 5355498 | 1785 | 0.45625 | 0.01785 | 0.9125
5355513 | 지상 4층 | 지상 4층 | 5355498 | 1810 | 0.4625 | 0.0181 | 0.925
5355514 | 지상 4층 | 지상 4층 | 5355498 | 1810 | 0.4625 | 0.0181 | 0.925
5355515 | 지상 4층 | 지상 4층 | 5355498 | 2100 | 0.535 | 0.021 | 1.06
5355516 | 지상 4층 | 지상 4층 | 5355498 | 520 | 0.14 | 0.0052 | 0.27
5355520 | 지상 4층 | 지상 4층 | 5355498 | 1810 | 0.4625 | 0.0181 | 0.925
5355522 | 지상 4층 | 지상 4층 | 5355498 | 1500 | 0.385 | 0.015 | 0.77
5355523 | 지상 4층 | 지상 4층 | 5355498 | 2100 | 0.535 | 0.021 | 1.06
5355524 | 지상 4층 | 지상 4층 | 5355498 | 520 | 0.14 | 0.0052 | 0.27
5355528 | 지상 4층 | 지상 4층 | 5355498 | 1500 | 0.385 | 0.015 | 0.77
5355529 | 지상 4층 | 지상 4층 | 5355498 | 2420 | 0.615 | 0.0242 | 1.23
5355530 | 지상 4층 | 지상 4층 | 5355498 | 2420 | 0.615 | 0.0242 | 1.23
5355531 | 지상 4층 | 지상 4층 | 5355498 | 2100 | 0.535 | 0.021 | 1.06
5355532 | 지상 4층 | 지상 4층 | 5355498 | 520 | 0.14 | 0.0052 | 0.27
5355536 | 지상 4층 | 지상 4층 | 5355498 | 2420 | 0.615 | 0.0242 | 1.23
5355537 | 지상 4층 | 지상 4층 | 5355498 | 2085 | 0.53125 | 0.02085 | 1.0625
5355538 | 지상 4층 | 지상 4층 | 5355498 | 2085 | 0.53125 | 0.02085 | 1.0625
5355539 | 지상 4층 | 지상 4층 | 5355498 | 2100 | 0.535 | 0.021 | 1.06
5355540 | 지상 4층 | 지상 4층 | 5355498 | 520 | 0.14 | 0.0052 | 0.27
5389072 | 지상 4층 | 지상 4층 | 5389070 | 2085 | 0.53125 | 0.02085 | 1.0625
5389073 | 지상 4층 | 지상 4층 | 5389070 | 2085 | 0.53125 | 0.02085 | 1.0625
5389075 | 지상 4층 | 지상 4층 | 5389070 | 520 | 0.14 | 0.0052 | 0.27
5389091 | 지상 4층 | 지상 4층 | 5389070 | 2100 | 0.535 | 0.021 | 1.06
5389092 | 지상 4층 | 지상 4층 | 5389070 | 2085 | 0.53125 | 0.02085 | 1.0625
5389522 | 지상 4층 | 지상 4층 | 5389520 | 490.035 | 0.132509 | 0.00490035 | 0.265017
5389528 | 지상 4층 | 지상 4층 | 5389520 | 500 | 0.135 | 0.005 | 0.27
5389530 | 지상 4층 | 지상 4층 | 5389520 | 2100 | 0.535 | 0.021 | 1.06
5389536 | 지상 4층 | 지상 4층 | 5389520 | 500 | 0.135 | 0.005 | 0.27
5389537 | 지상 4층 | 지상 4층 | 5389520 | 1500 | 0.385 | 0.015 | 0.77
5389538 | 지상 4층 | 지상 4층 | 5389520 | 520 | 0.14 | 0.0052 | 0.27
5389542 | 지상 4층 | 지상 4층 | 5389520 | 1500 | 0.385 | 0.015 | 0.77
5389544 | 지상 4층 | 지상 4층 | 5389520 | 490.035 | 0.132509 | 0.00490035 | 0.265017
5389545 | 지상 4층 | 지상 4층 | 5389520 | 2100 | 0.535 | 0.021 | 1.06
5389546 | 지상 4층 | 지상 4층 | 5389520 | 520 | 0.14 | 0.0052 | 0.27
5393179 | 지상 9층 | 지상 9층 | 5393177 | 2150 | 0.5475 | 0.0215 | 1.095
5393180 | 지상 9층 | 지상 9층 | 5393177 | 2150 | 0.5475 | 0.0215 | 1.095
5393182 | 지상 9층 | 지상 9층 | 5393177 | 920 | 0.24 | 0.0092 | 0.47
5393198 | 지상 9층 | 지상 9층 | 5393177 | 2100 | 0.535 | 0.021 | 1.06
5393199 | 지상 9층 | 지상 9층 | 5393177 | 2150 | 0.5475 | 0.0215 | 1.095
5393185 | 지상 9층 | 지상 9층 | 5393183 | 535.034 | 0.143758 | 0.00535034 | 0.287517
5393202 | 지상 9층 | 지상 9층 | 5393183 | 454.965 | 0.123741 | 0.00454965 | 0.247483
5393204 | 지상 9층 | 지상 9층 | 5393183 | 2100 | 0.535 | 0.021 | 1.06
5393210 | 지상 9층 | 지상 9층 | 5393183 | 454.965 | 0.123741 | 0.00454965 | 0.247483
5393211 | 지상 9층 | 지상 9층 | 5393183 | 1500 | 0.385 | 0.015 | 0.77
5393212 | 지상 9층 | 지상 9층 | 5393183 | 920 | 0.24 | 0.0092 | 0.47
5393216 | 지상 9층 | 지상 9층 | 5393183 | 1500 | 0.385 | 0.015 | 0.77
5393218 | 지상 9층 | 지상 9층 | 5393183 | 535.034 | 0.143758 | 0.00535034 | 0.287517
5393219 | 지상 9층 | 지상 9층 | 5393183 | 2100 | 0.535 | 0.021 | 1.06
5393220 | 지상 9층 | 지상 9층 | 5393183 | 920 | 0.24 | 0.0092 | 0.47
5393191 | 지상 9층 | 지상 9층 | 5393189 | 280.009 | 0.0800022 | 0.00280009 | 0.160004
5393193 | 지상 9층 | 지상 9층 | 5393189 | 2100 | 0.535 | 0.021 | 1.06
5393223 | 지상 9층 | 지상 9층 | 5393189 | 920 | 0.24 | 0.0092 | 0.47
5393225 | 지상 9층 | 지상 9층 | 5393189 | 759.991 | 0.199998 | 0.00759991 | 0.399996
5393229 | 지상 9층 | 지상 9층 | 5393189 | 759.991 | 0.199998 | 0.00759991 | 0.399996
5393231 | 지상 9층 | 지상 9층 | 5393189 | 1495 | 0.38375 | 0.01495 | 0.7675
5393232 | 지상 9층 | 지상 9층 | 5393189 | 2100 | 0.535 | 0.021 | 1.06
5393233 | 지상 9층 | 지상 9층 | 5393189 | 920 | 0.24 | 0.0092 | 0.47
7696740 | 지상 9층 | 지상 9층 | 5393189 | 1495 | 0.38375 | 0.01495 | 0.7675
7696741 | 지상 9층 | 지상 9층 | 5393189 | 280.009 | 0.0800022 | 0.00280009 | 0.160004
5396621 | 지상 5층 | 지상 5층 | 5396619 | 423.127 | 0.115782 | 0.00423127 | 0.231564
5396623 | 지상 5층 | 지상 5층 | 5396619 | 2100 | 0.535 | 0.021 | 1.06
5396624 | 지상 5층 | 지상 5층 | 5396619 | 520 | 0.14 | 0.0052 | 0.27
5396627 | 지상 5층 | 지상 5층 | 5396619 | 520 | 0.14 | 0.0052 | 0.27
5396628 | 지상 5층 | 지상 5층 | 5396619 | 2100 | 0.535 | 0.021 | 1.06
5396629 | 지상 5층 | 지상 5층 | 5396619 | 426.838 | 0.116709 | 0.00426838 | 0.233419
5396633 | 지상 5층 | 지상 5층 | 5396619 | 426.838 | 0.116709 | 0.00426838 | 0.233419
5396635 | 지상 5층 | 지상 5층 | 5396619 | 1450 | 0.3725 | 0.0145 | 0.745
5396636 | 지상 5층 | 지상 5층 | 5396619 | 2100 | 0.535 | 0.021 | 1.06
5396637 | 지상 5층 | 지상 5층 | 5396619 | 520 | 0.14 | 0.0052 | 0.27
5396641 | 지상 5층 | 지상 5층 | 5396619 | 1450 | 0.3725 | 0.0145 | 0.745
5396643 | 지상 5층 | 지상 5층 | 5396619 | 423.127 | 0.115782 | 0.00423127 | 0.231564
5396644 | 지상 5층 | 지상 5층 | 5396619 | 2100 | 0.535 | 0.021 | 1.06
5396645 | 지상 5층 | 지상 5층 | 5396619 | 520 | 0.14 | 0.0052 | 0.27
5396650 | 지상 6층 | 지상 6층 | 5396648 | 423.127 | 0.115782 | 0.00423127 | 0.231564
5396652 | 지상 6층 | 지상 6층 | 5396648 | 2100 | 0.535 | 0.021 | 1.06
5396653 | 지상 6층 | 지상 6층 | 5396648 | 520 | 0.14 | 0.0052 | 0.27
5396656 | 지상 6층 | 지상 6층 | 5396648 | 520 | 0.14 | 0.0052 | 0.27
5396657 | 지상 6층 | 지상 6층 | 5396648 | 2100 | 0.535 | 0.021 | 1.06
5396658 | 지상 6층 | 지상 6층 | 5396648 | 426.838 | 0.116709 | 0.00426838 | 0.233419
5396662 | 지상 6층 | 지상 6층 | 5396648 | 426.838 | 0.116709 | 0.00426838 | 0.233419
5396664 | 지상 6층 | 지상 6층 | 5396648 | 1450 | 0.3725 | 0.0145 | 0.745
5396665 | 지상 6층 | 지상 6층 | 5396648 | 2100 | 0.535 | 0.021 | 1.06
5396666 | 지상 6층 | 지상 6층 | 5396648 | 520 | 0.14 | 0.0052 | 0.27
5396670 | 지상 6층 | 지상 6층 | 5396648 | 1450 | 0.3725 | 0.0145 | 0.745
5396672 | 지상 6층 | 지상 6층 | 5396648 | 423.127 | 0.115782 | 0.00423127 | 0.231564
5396673 | 지상 6층 | 지상 6층 | 5396648 | 2100 | 0.535 | 0.021 | 1.06
5396674 | 지상 6층 | 지상 6층 | 5396648 | 520 | 0.14 | 0.0052 | 0.27
5396679 | 지상 7층 | 지상 7층 | 5396677 | 423.127 | 0.115782 | 0.00423127 | 0.231564
5396681 | 지상 7층 | 지상 7층 | 5396677 | 2100 | 0.535 | 0.021 | 1.06
5396682 | 지상 7층 | 지상 7층 | 5396677 | 520 | 0.14 | 0.0052 | 0.27
5396685 | 지상 7층 | 지상 7층 | 5396677 | 520 | 0.14 | 0.0052 | 0.27
5396686 | 지상 7층 | 지상 7층 | 5396677 | 2100 | 0.535 | 0.021 | 1.06
5396687 | 지상 7층 | 지상 7층 | 5396677 | 426.838 | 0.116709 | 0.00426838 | 0.233419
5396691 | 지상 7층 | 지상 7층 | 5396677 | 426.838 | 0.116709 | 0.00426838 | 0.233419
5396693 | 지상 7층 | 지상 7층 | 5396677 | 1450 | 0.3725 | 0.0145 | 0.745
5396694 | 지상 7층 | 지상 7층 | 5396677 | 2100 | 0.535 | 0.021 | 1.06
5396695 | 지상 7층 | 지상 7층 | 5396677 | 520 | 0.14 | 0.0052 | 0.27
5396699 | 지상 7층 | 지상 7층 | 5396677 | 1450 | 0.3725 | 0.0145 | 0.745
5396701 | 지상 7층 | 지상 7층 | 5396677 | 423.127 | 0.115782 | 0.00423127 | 0.231564
5396702 | 지상 7층 | 지상 7층 | 5396677 | 2100 | 0.535 | 0.021 | 1.06
5396703 | 지상 7층 | 지상 7층 | 5396677 | 520 | 0.14 | 0.0052 | 0.27
5396708 | 지상 8층 | 지상 8층 | 5396706 | 425 | 0.11625 | 0.00425 | 0.2325
5396710 | 지상 8층 | 지상 8층 | 5396706 | 2100 | 0.535 | 0.021 | 1.06
5396711 | 지상 8층 | 지상 8층 | 5396706 | 520 | 0.14 | 0.0052 | 0.27
5396714 | 지상 8층 | 지상 8층 | 5396706 | 520 | 0.14 | 0.0052 | 0.27
5396715 | 지상 8층 | 지상 8층 | 5396706 | 2100 | 0.535 | 0.021 | 1.06
5396716 | 지상 8층 | 지상 8층 | 5396706 | 425 | 0.11625 | 0.00425 | 0.2325
5396720 | 지상 8층 | 지상 8층 | 5396706 | 425 | 0.11625 | 0.00425 | 0.2325
5396722 | 지상 8층 | 지상 8층 | 5396706 | 1450 | 0.3725 | 0.0145 | 0.745
5396723 | 지상 8층 | 지상 8층 | 5396706 | 2100 | 0.535 | 0.021 | 1.06
5396724 | 지상 8층 | 지상 8층 | 5396706 | 520 | 0.14 | 0.0052 | 0.27
5396728 | 지상 8층 | 지상 8층 | 5396706 | 1450 | 0.3725 | 0.0145 | 0.745
5396730 | 지상 8층 | 지상 8층 | 5396706 | 425 | 0.11625 | 0.00425 | 0.2325
5396731 | 지상 8층 | 지상 8층 | 5396706 | 2100 | 0.535 | 0.021 | 1.06
5396732 | 지상 8층 | 지상 8층 | 5396706 | 520 | 0.14 | 0.0052 | 0.27
5397133 | 지상 5층 | 지상 5층 | 5397131 | 2534.97 | 0.643741 | 0.0253497 | 1.28748
5397135 | 지상 5층 | 지상 5층 | 5397131 | 2100 | 0.535 | 0.021 | 1.06
5397136 | 지상 5층 | 지상 5층 | 5397131 | 520 | 0.14 | 0.0052 | 0.27
5397139 | 지상 5층 | 지상 5층 | 5397131 | 1500 | 0.385 | 0.015 | 0.77
5397141 | 지상 5층 | 지상 5층 | 5397131 | 2100 | 0.535 | 0.021 | 1.06
5397144 | 지상 5층 | 지상 5층 | 5397131 | 2265 | 0.57625 | 0.02265 | 1.1525
5397146 | 지상 5층 | 지상 5층 | 5397131 | 2100 | 0.535 | 0.021 | 1.06
5397151 | 지상 5층 | 지상 5층 | 5397131 | 520 | 0.14 | 0.0052 | 0.27
5397152 | 지상 5층 | 지상 5층 | 5397131 | 2100 | 0.535 | 0.021 | 1.06
5397153 | 지상 5층 | 지상 5층 | 5397131 | 2265 | 0.57625 | 0.02265 | 1.1525
5397154 | 지상 5층 | 지상 5층 | 5397131 | 1500 | 0.385 | 0.015 | 0.77
5397155 | 지상 5층 | 지상 5층 | 5397131 | 2534.97 | 0.643741 | 0.0253497 | 1.28748
5397156 | 지상 5층 | 지상 5층 | 5397131 | 520 | 0.14 | 0.0052 | 0.27
5397157 | 지상 5층 | 지상 5층 | 5397131 | 520 | 0.14 | 0.0052 | 0.27
5397160 | 지상 5층 | 지상 5층 | 5397158 | 2635 | 0.66875 | 0.02635 | 1.3375
5397162 | 지상 5층 | 지상 5층 | 5397158 | 2100 | 0.535 | 0.021 | 1.06
5397163 | 지상 5층 | 지상 5층 | 5397158 | 520 | 0.14 | 0.0052 | 0.27
5397166 | 지상 5층 | 지상 5층 | 5397158 | 1500 | 0.385 | 0.015 | 0.77
5397168 | 지상 5층 | 지상 5층 | 5397158 | 2100 | 0.535 | 0.021 | 1.06
5397171 | 지상 5층 | 지상 5층 | 5397158 | 2265 | 0.57625 | 0.02265 | 1.1525
5397173 | 지상 5층 | 지상 5층 | 5397158 | 2100 | 0.535 | 0.021 | 1.06
5397178 | 지상 5층 | 지상 5층 | 5397158 | 520 | 0.14 | 0.0052 | 0.27
5397179 | 지상 5층 | 지상 5층 | 5397158 | 2100 | 0.535 | 0.021 | 1.06
5397180 | 지상 5층 | 지상 5층 | 5397158 | 2265 | 0.57625 | 0.02265 | 1.1525
5397181 | 지상 5층 | 지상 5층 | 5397158 | 1500 | 0.385 | 0.015 | 0.77
5397182 | 지상 5층 | 지상 5층 | 5397158 | 2635 | 0.66875 | 0.02635 | 1.3375
5397183 | 지상 5층 | 지상 5층 | 5397158 | 520 | 0.14 | 0.0052 | 0.27
5397184 | 지상 5층 | 지상 5층 | 5397158 | 520 | 0.14 | 0.0052 | 0.27
5397189 | 지상 6층 | 지상 6층 | 5397187 | 2534.97 | 0.643741 | 0.0253497 | 1.28748
5397191 | 지상 6층 | 지상 6층 | 5397187 | 2100 | 0.535 | 0.021 | 1.06
5397192 | 지상 6층 | 지상 6층 | 5397187 | 520 | 0.14 | 0.0052 | 0.27
5397195 | 지상 6층 | 지상 6층 | 5397187 | 1500 | 0.385 | 0.015 | 0.77
5397197 | 지상 6층 | 지상 6층 | 5397187 | 2100 | 0.535 | 0.021 | 1.06
5397200 | 지상 6층 | 지상 6층 | 5397187 | 2265 | 0.57625 | 0.02265 | 1.1525
5397202 | 지상 6층 | 지상 6층 | 5397187 | 2100 | 0.535 | 0.021 | 1.06
5397207 | 지상 6층 | 지상 6층 | 5397187 | 520 | 0.14 | 0.0052 | 0.27
5397208 | 지상 6층 | 지상 6층 | 5397187 | 2100 | 0.535 | 0.021 | 1.06
5397209 | 지상 6층 | 지상 6층 | 5397187 | 2265 | 0.57625 | 0.02265 | 1.1525
5397210 | 지상 6층 | 지상 6층 | 5397187 | 1500 | 0.385 | 0.015 | 0.77
5397211 | 지상 6층 | 지상 6층 | 5397187 | 2534.97 | 0.643741 | 0.0253497 | 1.28748
5397212 | 지상 6층 | 지상 6층 | 5397187 | 520 | 0.14 | 0.0052 | 0.27
5397213 | 지상 6층 | 지상 6층 | 5397187 | 520 | 0.14 | 0.0052 | 0.27
5397216 | 지상 6층 | 지상 6층 | 5397214 | 2635 | 0.66875 | 0.02635 | 1.3375
5397218 | 지상 6층 | 지상 6층 | 5397214 | 2100 | 0.535 | 0.021 | 1.06
5397219 | 지상 6층 | 지상 6층 | 5397214 | 520 | 0.14 | 0.0052 | 0.27
5397222 | 지상 6층 | 지상 6층 | 5397214 | 1500 | 0.385 | 0.015 | 0.77
5397224 | 지상 6층 | 지상 6층 | 5397214 | 2100 | 0.535 | 0.021 | 1.06
5397227 | 지상 6층 | 지상 6층 | 5397214 | 2265 | 0.57625 | 0.02265 | 1.1525
5397229 | 지상 6층 | 지상 6층 | 5397214 | 2100 | 0.535 | 0.021 | 1.06
5397234 | 지상 6층 | 지상 6층 | 5397214 | 520 | 0.14 | 0.0052 | 0.27
5397235 | 지상 6층 | 지상 6층 | 5397214 | 2100 | 0.535 | 0.021 | 1.06
5397236 | 지상 6층 | 지상 6층 | 5397214 | 2265 | 0.57625 | 0.02265 | 1.1525
5397237 | 지상 6층 | 지상 6층 | 5397214 | 1500 | 0.385 | 0.015 | 0.77
5397238 | 지상 6층 | 지상 6층 | 5397214 | 2635 | 0.66875 | 0.02635 | 1.3375
5397239 | 지상 6층 | 지상 6층 | 5397214 | 520 | 0.14 | 0.0052 | 0.27
5397240 | 지상 6층 | 지상 6층 | 5397214 | 520 | 0.14 | 0.0052 | 0.27
5397245 | 지상 7층 | 지상 7층 | 5397243 | 2529.97 | 0.642491 | 0.0252997 | 1.28498
5397247 | 지상 7층 | 지상 7층 | 5397243 | 2100 | 0.535 | 0.021 | 1.06
5397248 | 지상 7층 | 지상 7층 | 5397243 | 520 | 0.14 | 0.0052 | 0.27
5397251 | 지상 7층 | 지상 7층 | 5397243 | 1500 | 0.385 | 0.015 | 0.77
5397253 | 지상 7층 | 지상 7층 | 5397243 | 2100 | 0.535 | 0.021 | 1.06
5397256 | 지상 7층 | 지상 7층 | 5397243 | 2265 | 0.57625 | 0.02265 | 1.1525
5397258 | 지상 7층 | 지상 7층 | 5397243 | 2100 | 0.535 | 0.021 | 1.06
5397263 | 지상 7층 | 지상 7층 | 5397243 | 520 | 0.14 | 0.0052 | 0.27
5397264 | 지상 7층 | 지상 7층 | 5397243 | 2100 | 0.535 | 0.021 | 1.06
5397265 | 지상 7층 | 지상 7층 | 5397243 | 2265 | 0.57625 | 0.02265 | 1.1525
5397266 | 지상 7층 | 지상 7층 | 5397243 | 1500 | 0.385 | 0.015 | 0.77
5397267 | 지상 7층 | 지상 7층 | 5397243 | 2529.97 | 0.642491 | 0.0252997 | 1.28498
5397268 | 지상 7층 | 지상 7층 | 5397243 | 520 | 0.14 | 0.0052 | 0.27
5397269 | 지상 7층 | 지상 7층 | 5397243 | 520 | 0.14 | 0.0052 | 0.27
5397272 | 지상 7층 | 지상 7층 | 5397270 | 2635 | 0.66875 | 0.02635 | 1.3375
5397274 | 지상 7층 | 지상 7층 | 5397270 | 2100 | 0.535 | 0.021 | 1.06
5397275 | 지상 7층 | 지상 7층 | 5397270 | 520 | 0.14 | 0.0052 | 0.27
5397278 | 지상 7층 | 지상 7층 | 5397270 | 1500 | 0.385 | 0.015 | 0.77
5397280 | 지상 7층 | 지상 7층 | 5397270 | 2100 | 0.535 | 0.021 | 1.06
5397283 | 지상 7층 | 지상 7층 | 5397270 | 2265 | 0.57625 | 0.02265 | 1.1525
5397285 | 지상 7층 | 지상 7층 | 5397270 | 2100 | 0.535 | 0.021 | 1.06
5397290 | 지상 7층 | 지상 7층 | 5397270 | 520 | 0.14 | 0.0052 | 0.27
5397291 | 지상 7층 | 지상 7층 | 5397270 | 2100 | 0.535 | 0.021 | 1.06
5397292 | 지상 7층 | 지상 7층 | 5397270 | 2265 | 0.57625 | 0.02265 | 1.1525
5397293 | 지상 7층 | 지상 7층 | 5397270 | 1500 | 0.385 | 0.015 | 0.77
5397294 | 지상 7층 | 지상 7층 | 5397270 | 2635 | 0.66875 | 0.02635 | 1.3375
5397295 | 지상 7층 | 지상 7층 | 5397270 | 520 | 0.14 | 0.0052 | 0.27
5397296 | 지상 7층 | 지상 7층 | 5397270 | 520 | 0.14 | 0.0052 | 0.27
5397301 | 지상 8층 | 지상 8층 | 5397299 | 2534.97 | 0.643741 | 0.0253497 | 1.28748
5397303 | 지상 8층 | 지상 8층 | 5397299 | 2100 | 0.535 | 0.021 | 1.06
5397304 | 지상 8층 | 지상 8층 | 5397299 | 520 | 0.14 | 0.0052 | 0.27
5397307 | 지상 8층 | 지상 8층 | 5397299 | 1500 | 0.385 | 0.015 | 0.77
5397309 | 지상 8층 | 지상 8층 | 5397299 | 2100 | 0.535 | 0.021 | 1.06
5397312 | 지상 8층 | 지상 8층 | 5397299 | 2265 | 0.57625 | 0.02265 | 1.1525
5397314 | 지상 8층 | 지상 8층 | 5397299 | 2100 | 0.535 | 0.021 | 1.06
5397319 | 지상 8층 | 지상 8층 | 5397299 | 520 | 0.14 | 0.0052 | 0.27
5397320 | 지상 8층 | 지상 8층 | 5397299 | 2100 | 0.535 | 0.021 | 1.06
5397321 | 지상 8층 | 지상 8층 | 5397299 | 2265 | 0.57625 | 0.02265 | 1.1525
5397322 | 지상 8층 | 지상 8층 | 5397299 | 1500 | 0.385 | 0.015 | 0.77
5397323 | 지상 8층 | 지상 8층 | 5397299 | 2534.97 | 0.643741 | 0.0253497 | 1.28748
5397324 | 지상 8층 | 지상 8층 | 5397299 | 520 | 0.14 | 0.0052 | 0.27
5397325 | 지상 8층 | 지상 8층 | 5397299 | 520 | 0.14 | 0.0052 | 0.27
5397328 | 지상 8층 | 지상 8층 | 5397326 | 2735.03 | 0.693759 | 0.0273503 | 1.38752
5397330 | 지상 8층 | 지상 8층 | 5397326 | 2100 | 0.535 | 0.021 | 1.06
5397331 | 지상 8층 | 지상 8층 | 5397326 | 520 | 0.14 | 0.0052 | 0.27
5397334 | 지상 8층 | 지상 8층 | 5397326 | 1500 | 0.385 | 0.015 | 0.77
5397336 | 지상 8층 | 지상 8층 | 5397326 | 2100 | 0.535 | 0.021 | 1.06
5397339 | 지상 8층 | 지상 8층 | 5397326 | 2365 | 0.60125 | 0.02365 | 1.2025
5397341 | 지상 8층 | 지상 8층 | 5397326 | 2100 | 0.535 | 0.021 | 1.06
5397346 | 지상 8층 | 지상 8층 | 5397326 | 520 | 0.14 | 0.0052 | 0.27
5397347 | 지상 8층 | 지상 8층 | 5397326 | 2100 | 0.535 | 0.021 | 1.06
5397348 | 지상 8층 | 지상 8층 | 5397326 | 2365 | 0.60125 | 0.02365 | 1.2025
5397349 | 지상 8층 | 지상 8층 | 5397326 | 1500 | 0.385 | 0.015 | 0.77
5397350 | 지상 8층 | 지상 8층 | 5397326 | 2735.03 | 0.693759 | 0.0273503 | 1.38752
5397351 | 지상 8층 | 지상 8층 | 5397326 | 520 | 0.14 | 0.0052 | 0.27
5397352 | 지상 8층 | 지상 8층 | 5397326 | 520 | 0.14 | 0.0052 | 0.27
5398143 | 지상 5층 | 지상 5층 | 5398141 | 423.145 | 0.115786 | 0.00423145 | 0.231573
5398145 | 지상 5층 | 지상 5층 | 5398141 | 2100 | 0.535 | 0.021 | 1.06
5398146 | 지상 5층 | 지상 5층 | 5398141 | 520 | 0.14 | 0.0052 | 0.27
5398149 | 지상 5층 | 지상 5층 | 5398141 | 520 | 0.14 | 0.0052 | 0.27
5398150 | 지상 5층 | 지상 5층 | 5398141 | 2100 | 0.535 | 0.021 | 1.06
5398151 | 지상 5층 | 지상 5층 | 5398141 | 376.847 | 0.104212 | 0.00376847 | 0.208423
5398155 | 지상 5층 | 지상 5층 | 5398141 | 376.847 | 0.104212 | 0.00376847 | 0.208423
5398157 | 지상 5층 | 지상 5층 | 5398141 | 1500 | 0.385 | 0.015 | 0.77
5398158 | 지상 5층 | 지상 5층 | 5398141 | 2100 | 0.535 | 0.021 | 1.06
5398159 | 지상 5층 | 지상 5층 | 5398141 | 520 | 0.14 | 0.0052 | 0.27
5398163 | 지상 5층 | 지상 5층 | 5398141 | 1500 | 0.385 | 0.015 | 0.77
5398165 | 지상 5층 | 지상 5층 | 5398141 | 423.145 | 0.115786 | 0.00423145 | 0.231573
5398166 | 지상 5층 | 지상 5층 | 5398141 | 2100 | 0.535 | 0.021 | 1.06
5398167 | 지상 5층 | 지상 5층 | 5398141 | 520 | 0.14 | 0.0052 | 0.27
5398172 | 지상 6층 | 지상 6층 | 5398170 | 423.145 | 0.115786 | 0.00423145 | 0.231573
5398174 | 지상 6층 | 지상 6층 | 5398170 | 2100 | 0.535 | 0.021 | 1.06
5398175 | 지상 6층 | 지상 6층 | 5398170 | 520 | 0.14 | 0.0052 | 0.27
5398178 | 지상 6층 | 지상 6층 | 5398170 | 520 | 0.14 | 0.0052 | 0.27
5398179 | 지상 6층 | 지상 6층 | 5398170 | 2100 | 0.535 | 0.021 | 1.06
5398180 | 지상 6층 | 지상 6층 | 5398170 | 376.847 | 0.104212 | 0.00376847 | 0.208423
5398184 | 지상 6층 | 지상 6층 | 5398170 | 376.847 | 0.104212 | 0.00376847 | 0.208423
5398186 | 지상 6층 | 지상 6층 | 5398170 | 1500 | 0.385 | 0.015 | 0.77
5398187 | 지상 6층 | 지상 6층 | 5398170 | 2100 | 0.535 | 0.021 | 1.06
5398188 | 지상 6층 | 지상 6층 | 5398170 | 520 | 0.14 | 0.0052 | 0.27
5398192 | 지상 6층 | 지상 6층 | 5398170 | 1500 | 0.385 | 0.015 | 0.77
5398194 | 지상 6층 | 지상 6층 | 5398170 | 423.145 | 0.115786 | 0.00423145 | 0.231573
5398195 | 지상 6층 | 지상 6층 | 5398170 | 2100 | 0.535 | 0.021 | 1.06
5398196 | 지상 6층 | 지상 6층 | 5398170 | 520 | 0.14 | 0.0052 | 0.27
5398201 | 지상 7층 | 지상 7층 | 5398199 | 468.145 | 0.127036 | 0.00468145 | 0.254073
5398203 | 지상 7층 | 지상 7층 | 5398199 | 2100 | 0.535 | 0.021 | 1.06
5398204 | 지상 7층 | 지상 7층 | 5398199 | 520 | 0.14 | 0.0052 | 0.27
5398207 | 지상 7층 | 지상 7층 | 5398199 | 520 | 0.14 | 0.0052 | 0.27
5398208 | 지상 7층 | 지상 7층 | 5398199 | 2100 | 0.535 | 0.021 | 1.06
5398209 | 지상 7층 | 지상 7층 | 5398199 | 375 | 0.10375 | 0.00375 | 0.2075
5398213 | 지상 7층 | 지상 7층 | 5398199 | 375 | 0.10375 | 0.00375 | 0.2075
5398215 | 지상 7층 | 지상 7층 | 5398199 | 1500 | 0.385 | 0.015 | 0.77
5398216 | 지상 7층 | 지상 7층 | 5398199 | 2100 | 0.535 | 0.021 | 1.06
5398217 | 지상 7층 | 지상 7층 | 5398199 | 520 | 0.14 | 0.0052 | 0.27
5398221 | 지상 7층 | 지상 7층 | 5398199 | 1500 | 0.385 | 0.015 | 0.77
5398223 | 지상 7층 | 지상 7층 | 5398199 | 468.145 | 0.127036 | 0.00468145 | 0.254073
5398224 | 지상 7층 | 지상 7층 | 5398199 | 2100 | 0.535 | 0.021 | 1.06
5398225 | 지상 7층 | 지상 7층 | 5398199 | 520 | 0.14 | 0.0052 | 0.27
5398230 | 지상 8층 | 지상 8층 | 5398228 | 423.145 | 0.115786 | 0.00423145 | 0.231573
5398232 | 지상 8층 | 지상 8층 | 5398228 | 2100 | 0.535 | 0.021 | 1.06
5398233 | 지상 8층 | 지상 8층 | 5398228 | 520 | 0.14 | 0.0052 | 0.27
5398236 | 지상 8층 | 지상 8층 | 5398228 | 520 | 0.14 | 0.0052 | 0.27
5398237 | 지상 8층 | 지상 8층 | 5398228 | 2100 | 0.535 | 0.021 | 1.06
5398238 | 지상 8층 | 지상 8층 | 5398228 | 376.847 | 0.104212 | 0.00376847 | 0.208423
5398242 | 지상 8층 | 지상 8층 | 5398228 | 376.847 | 0.104212 | 0.00376847 | 0.208423
5398244 | 지상 8층 | 지상 8층 | 5398228 | 1500 | 0.385 | 0.015 | 0.77
5398245 | 지상 8층 | 지상 8층 | 5398228 | 2100 | 0.535 | 0.021 | 1.06
5398246 | 지상 8층 | 지상 8층 | 5398228 | 520 | 0.14 | 0.0052 | 0.27
5398250 | 지상 8층 | 지상 8층 | 5398228 | 1500 | 0.385 | 0.015 | 0.77
5398252 | 지상 8층 | 지상 8층 | 5398228 | 423.145 | 0.115786 | 0.00423145 | 0.231573
5398253 | 지상 8층 | 지상 8층 | 5398228 | 2100 | 0.535 | 0.021 | 1.06
5398254 | 지상 8층 | 지상 8층 | 5398228 | 520 | 0.14 | 0.0052 | 0.27
5398674 | 지상 5층 | 지상 5층 | 5398672 | 2085 | 0.53125 | 0.02085 | 1.0625
5398676 | 지상 5층 | 지상 5층 | 5398672 | 2100 | 0.535 | 0.021 | 1.06
5398677 | 지상 5층 | 지상 5층 | 5398672 | 520 | 0.14 | 0.0052 | 0.27
5398680 | 지상 5층 | 지상 5층 | 5398672 | 520 | 0.14 | 0.0052 | 0.27
5398681 | 지상 5층 | 지상 5층 | 5398672 | 2100 | 0.535 | 0.021 | 1.06
5398682 | 지상 5층 | 지상 5층 | 5398672 | 1785 | 0.45625 | 0.01785 | 0.9125
5398686 | 지상 5층 | 지상 5층 | 5398672 | 1785 | 0.45625 | 0.01785 | 0.9125
5398688 | 지상 5층 | 지상 5층 | 5398672 | 1810 | 0.4625 | 0.0181 | 0.925
5398689 | 지상 5층 | 지상 5층 | 5398672 | 2100 | 0.535 | 0.021 | 1.06
5398690 | 지상 5층 | 지상 5층 | 5398672 | 520 | 0.14 | 0.0052 | 0.27
5398694 | 지상 5층 | 지상 5층 | 5398672 | 1810 | 0.4625 | 0.0181 | 0.925
5398696 | 지상 5층 | 지상 5층 | 5398672 | 1500 | 0.385 | 0.015 | 0.77
5398697 | 지상 5층 | 지상 5층 | 5398672 | 2100 | 0.535 | 0.021 | 1.06
5398698 | 지상 5층 | 지상 5층 | 5398672 | 520 | 0.14 | 0.0052 | 0.27
5398702 | 지상 5층 | 지상 5층 | 5398672 | 1500 | 0.385 | 0.015 | 0.77
5398704 | 지상 5층 | 지상 5층 | 5398672 | 2420 | 0.615 | 0.0242 | 1.23
5398705 | 지상 5층 | 지상 5층 | 5398672 | 2100 | 0.535 | 0.021 | 1.06
5398706 | 지상 5층 | 지상 5층 | 5398672 | 520 | 0.14 | 0.0052 | 0.27
5398710 | 지상 5층 | 지상 5층 | 5398672 | 2420 | 0.615 | 0.0242 | 1.23
5398712 | 지상 5층 | 지상 5층 | 5398672 | 2085 | 0.53125 | 0.02085 | 1.0625
5398713 | 지상 5층 | 지상 5층 | 5398672 | 2100 | 0.535 | 0.021 | 1.06
5398714 | 지상 5층 | 지상 5층 | 5398672 | 520 | 0.14 | 0.0052 | 0.27
5398719 | 지상 6층 | 지상 6층 | 5398717 | 2085 | 0.53125 | 0.02085 | 1.0625
5398721 | 지상 6층 | 지상 6층 | 5398717 | 2100 | 0.535 | 0.021 | 1.06
5398722 | 지상 6층 | 지상 6층 | 5398717 | 520 | 0.14 | 0.0052 | 0.27
5398725 | 지상 6층 | 지상 6층 | 5398717 | 520 | 0.14 | 0.0052 | 0.27
5398726 | 지상 6층 | 지상 6층 | 5398717 | 2100 | 0.535 | 0.021 | 1.06
5398727 | 지상 6층 | 지상 6층 | 5398717 | 1785 | 0.45625 | 0.01785 | 0.9125
5398731 | 지상 6층 | 지상 6층 | 5398717 | 1785 | 0.45625 | 0.01785 | 0.9125
5398733 | 지상 6층 | 지상 6층 | 5398717 | 1810 | 0.4625 | 0.0181 | 0.925
5398734 | 지상 6층 | 지상 6층 | 5398717 | 2100 | 0.535 | 0.021 | 1.06
5398735 | 지상 6층 | 지상 6층 | 5398717 | 520 | 0.14 | 0.0052 | 0.27
5398739 | 지상 6층 | 지상 6층 | 5398717 | 1810 | 0.4625 | 0.0181 | 0.925
5398741 | 지상 6층 | 지상 6층 | 5398717 | 1500 | 0.385 | 0.015 | 0.77
5398742 | 지상 6층 | 지상 6층 | 5398717 | 2100 | 0.535 | 0.021 | 1.06
5398743 | 지상 6층 | 지상 6층 | 5398717 | 520 | 0.14 | 0.0052 | 0.27
5398747 | 지상 6층 | 지상 6층 | 5398717 | 1500 | 0.385 | 0.015 | 0.77
5398749 | 지상 6층 | 지상 6층 | 5398717 | 2420 | 0.615 | 0.0242 | 1.23
5398750 | 지상 6층 | 지상 6층 | 5398717 | 2100 | 0.535 | 0.021 | 1.06
5398751 | 지상 6층 | 지상 6층 | 5398717 | 520 | 0.14 | 0.0052 | 0.27
5398755 | 지상 6층 | 지상 6층 | 5398717 | 2420 | 0.615 | 0.0242 | 1.23
5398757 | 지상 6층 | 지상 6층 | 5398717 | 2085 | 0.53125 | 0.02085 | 1.0625
5398758 | 지상 6층 | 지상 6층 | 5398717 | 2100 | 0.535 | 0.021 | 1.06
5398759 | 지상 6층 | 지상 6층 | 5398717 | 520 | 0.14 | 0.0052 | 0.27
5398764 | 지상 7층 | 지상 7층 | 5398762 | 2085 | 0.53125 | 0.02085 | 1.0625
5398766 | 지상 7층 | 지상 7층 | 5398762 | 2100 | 0.535 | 0.021 | 1.06
5398767 | 지상 7층 | 지상 7층 | 5398762 | 520 | 0.14 | 0.0052 | 0.27
5398770 | 지상 7층 | 지상 7층 | 5398762 | 520 | 0.14 | 0.0052 | 0.27
5398771 | 지상 7층 | 지상 7층 | 5398762 | 2100 | 0.535 | 0.021 | 1.06
5398772 | 지상 7층 | 지상 7층 | 5398762 | 1785 | 0.45625 | 0.01785 | 0.9125
5398776 | 지상 7층 | 지상 7층 | 5398762 | 1785 | 0.45625 | 0.01785 | 0.9125
5398778 | 지상 7층 | 지상 7층 | 5398762 | 1810 | 0.4625 | 0.0181 | 0.925
5398779 | 지상 7층 | 지상 7층 | 5398762 | 2100 | 0.535 | 0.021 | 1.06
5398780 | 지상 7층 | 지상 7층 | 5398762 | 520 | 0.14 | 0.0052 | 0.27
5398784 | 지상 7층 | 지상 7층 | 5398762 | 1810 | 0.4625 | 0.0181 | 0.925
5398786 | 지상 7층 | 지상 7층 | 5398762 | 1500 | 0.385 | 0.015 | 0.77
5398787 | 지상 7층 | 지상 7층 | 5398762 | 2100 | 0.535 | 0.021 | 1.06
5398788 | 지상 7층 | 지상 7층 | 5398762 | 520 | 0.14 | 0.0052 | 0.27
5398792 | 지상 7층 | 지상 7층 | 5398762 | 1500 | 0.385 | 0.015 | 0.77
5398794 | 지상 7층 | 지상 7층 | 5398762 | 2420 | 0.615 | 0.0242 | 1.23
5398795 | 지상 7층 | 지상 7층 | 5398762 | 2100 | 0.535 | 0.021 | 1.06
5398796 | 지상 7층 | 지상 7층 | 5398762 | 520 | 0.14 | 0.0052 | 0.27
5398800 | 지상 7층 | 지상 7층 | 5398762 | 2420 | 0.615 | 0.0242 | 1.23
5398802 | 지상 7층 | 지상 7층 | 5398762 | 2085 | 0.53125 | 0.02085 | 1.0625
5398803 | 지상 7층 | 지상 7층 | 5398762 | 2100 | 0.535 | 0.021 | 1.06
5398804 | 지상 7층 | 지상 7층 | 5398762 | 520 | 0.14 | 0.0052 | 0.27
5398809 | 지상 8층 | 지상 8층 | 5398807 | 2085 | 0.53125 | 0.02085 | 1.0625
5398811 | 지상 8층 | 지상 8층 | 5398807 | 2100 | 0.535 | 0.021 | 1.06
5398812 | 지상 8층 | 지상 8층 | 5398807 | 520 | 0.14 | 0.0052 | 0.27
5398815 | 지상 8층 | 지상 8층 | 5398807 | 520 | 0.14 | 0.0052 | 0.27
5398816 | 지상 8층 | 지상 8층 | 5398807 | 2100 | 0.535 | 0.021 | 1.06
5398817 | 지상 8층 | 지상 8층 | 5398807 | 1885 | 0.48125 | 0.01885 | 0.9625
5398821 | 지상 8층 | 지상 8층 | 5398807 | 1885 | 0.48125 | 0.01885 | 0.9625
5398823 | 지상 8층 | 지상 8층 | 5398807 | 1810 | 0.4625 | 0.0181 | 0.925
5398824 | 지상 8층 | 지상 8층 | 5398807 | 2100 | 0.535 | 0.021 | 1.06
5398825 | 지상 8층 | 지상 8층 | 5398807 | 520 | 0.14 | 0.0052 | 0.27
5398829 | 지상 8층 | 지상 8층 | 5398807 | 1810 | 0.4625 | 0.0181 | 0.925
5398831 | 지상 8층 | 지상 8층 | 5398807 | 1500 | 0.385 | 0.015 | 0.77
5398832 | 지상 8층 | 지상 8층 | 5398807 | 2100 | 0.535 | 0.021 | 1.06
5398833 | 지상 8층 | 지상 8층 | 5398807 | 520 | 0.14 | 0.0052 | 0.27
5398837 | 지상 8층 | 지상 8층 | 5398807 | 1500 | 0.385 | 0.015 | 0.77
5398839 | 지상 8층 | 지상 8층 | 5398807 | 2420 | 0.615 | 0.0242 | 1.23
5398840 | 지상 8층 | 지상 8층 | 5398807 | 2100 | 0.535 | 0.021 | 1.06
5398841 | 지상 8층 | 지상 8층 | 5398807 | 520 | 0.14 | 0.0052 | 0.27
5398845 | 지상 8층 | 지상 8층 | 5398807 | 2420 | 0.615 | 0.0242 | 1.23
5398847 | 지상 8층 | 지상 8층 | 5398807 | 2085 | 0.53125 | 0.02085 | 1.0625
5398848 | 지상 8층 | 지상 8층 | 5398807 | 2100 | 0.535 | 0.021 | 1.06
5398849 | 지상 8층 | 지상 8층 | 5398807 | 520 | 0.14 | 0.0052 | 0.27
5403430 | 지상 5층 | 지상 5층 | 5403428 | 2045 | 0.52125 | 0.02045 | 1.0425
5403431 | 지상 5층 | 지상 5층 | 5403428 | 2045 | 0.52125 | 0.02045 | 1.0425
5403433 | 지상 5층 | 지상 5층 | 5403428 | 520 | 0.14 | 0.0052 | 0.27
5403437 | 지상 5층 | 지상 5층 | 5403428 | 2100 | 0.535 | 0.021 | 1.06
5403438 | 지상 5층 | 지상 5층 | 5403428 | 2045 | 0.52125 | 0.02045 | 1.0425
5403441 | 지상 5층 | 지상 5층 | 5403439 | 540.035 | 0.145009 | 0.00540035 | 0.290017
5403447 | 지상 5층 | 지상 5층 | 5403439 | 451.025 | 0.122756 | 0.00451025 | 0.245513
5403449 | 지상 5층 | 지상 5층 | 5403439 | 2100 | 0.535 | 0.021 | 1.06
5403455 | 지상 5층 | 지상 5층 | 5403439 | 451.025 | 0.122756 | 0.00451025 | 0.245513
5403456 | 지상 5층 | 지상 5층 | 5403439 | 1500 | 0.385 | 0.015 | 0.77
5403457 | 지상 5층 | 지상 5층 | 5403439 | 520 | 0.14 | 0.0052 | 0.27
5403461 | 지상 5층 | 지상 5층 | 5403439 | 1500 | 0.385 | 0.015 | 0.77
5403463 | 지상 5층 | 지상 5층 | 5403439 | 540.035 | 0.145009 | 0.00540035 | 0.290017
5403464 | 지상 5층 | 지상 5층 | 5403439 | 2100 | 0.535 | 0.021 | 1.06
5403465 | 지상 5층 | 지상 5층 | 5403439 | 520 | 0.14 | 0.0052 | 0.27
5403468 | 지상 6층 | 지상 6층 | 5403466 | 2045 | 0.52125 | 0.02045 | 1.0425
5403469 | 지상 6층 | 지상 6층 | 5403466 | 2045 | 0.52125 | 0.02045 | 1.0425
5403471 | 지상 6층 | 지상 6층 | 5403466 | 520 | 0.14 | 0.0052 | 0.27
5403475 | 지상 6층 | 지상 6층 | 5403466 | 2100 | 0.535 | 0.021 | 1.06
5403476 | 지상 6층 | 지상 6층 | 5403466 | 2045 | 0.52125 | 0.02045 | 1.0425
5403479 | 지상 6층 | 지상 6층 | 5403477 | 445.035 | 0.121259 | 0.00445035 | 0.242517
5403485 | 지상 6층 | 지상 6층 | 5403477 | 449.965 | 0.122491 | 0.00449965 | 0.244983
5403487 | 지상 6층 | 지상 6층 | 5403477 | 2100 | 0.535 | 0.021 | 1.06
5403493 | 지상 6층 | 지상 6층 | 5403477 | 449.965 | 0.122491 | 0.00449965 | 0.244983
5403494 | 지상 6층 | 지상 6층 | 5403477 | 1500 | 0.385 | 0.015 | 0.77
5403495 | 지상 6층 | 지상 6층 | 5403477 | 520 | 0.14 | 0.0052 | 0.27
5403499 | 지상 6층 | 지상 6층 | 5403477 | 1500 | 0.385 | 0.015 | 0.77
5403501 | 지상 6층 | 지상 6층 | 5403477 | 445.035 | 0.121259 | 0.00445035 | 0.242517
5403502 | 지상 6층 | 지상 6층 | 5403477 | 2100 | 0.535 | 0.021 | 1.06
5403503 | 지상 6층 | 지상 6층 | 5403477 | 520 | 0.14 | 0.0052 | 0.27
5403506 | 지상 7층 | 지상 7층 | 5403504 | 2050 | 0.5225 | 0.0205 | 1.045
5403507 | 지상 7층 | 지상 7층 | 5403504 | 2050 | 0.5225 | 0.0205 | 1.045
5403509 | 지상 7층 | 지상 7층 | 5403504 | 520 | 0.14 | 0.0052 | 0.27
5403513 | 지상 7층 | 지상 7층 | 5403504 | 2100 | 0.535 | 0.021 | 1.06
5403514 | 지상 7층 | 지상 7층 | 5403504 | 2050 | 0.5225 | 0.0205 | 1.045
5403517 | 지상 7층 | 지상 7층 | 5403515 | 445.035 | 0.121259 | 0.00445035 | 0.242517
5403523 | 지상 7층 | 지상 7층 | 5403515 | 454.965 | 0.123741 | 0.00454965 | 0.247483
5403525 | 지상 7층 | 지상 7층 | 5403515 | 2100 | 0.535 | 0.021 | 1.06
5403531 | 지상 7층 | 지상 7층 | 5403515 | 454.965 | 0.123741 | 0.00454965 | 0.247483
5403532 | 지상 7층 | 지상 7층 | 5403515 | 1500 | 0.385 | 0.015 | 0.77
5403533 | 지상 7층 | 지상 7층 | 5403515 | 520 | 0.14 | 0.0052 | 0.27
5403537 | 지상 7층 | 지상 7층 | 5403515 | 1500 | 0.385 | 0.015 | 0.77
5403539 | 지상 7층 | 지상 7층 | 5403515 | 445.035 | 0.121259 | 0.00445035 | 0.242517
5403540 | 지상 7층 | 지상 7층 | 5403515 | 2100 | 0.535 | 0.021 | 1.06
5403541 | 지상 7층 | 지상 7층 | 5403515 | 520 | 0.14 | 0.0052 | 0.27
5403544 | 지상 8층 | 지상 8층 | 5403542 | 2145.02 | 0.546254 | 0.0214502 | 1.09251
5403545 | 지상 8층 | 지상 8층 | 5403542 | 2145.02 | 0.546254 | 0.0214502 | 1.09251
5403547 | 지상 8층 | 지상 8층 | 5403542 | 520 | 0.14 | 0.0052 | 0.27
5403551 | 지상 8층 | 지상 8층 | 5403542 | 2100 | 0.535 | 0.021 | 1.06
5403552 | 지상 8층 | 지상 8층 | 5403542 | 2145.02 | 0.546254 | 0.0214502 | 1.09251
5403555 | 지상 8층 | 지상 8층 | 5403553 | 445.035 | 0.121259 | 0.00445035 | 0.242517
5403561 | 지상 8층 | 지상 8층 | 5403553 | 444.965 | 0.121241 | 0.00444965 | 0.242483
5403563 | 지상 8층 | 지상 8층 | 5403553 | 2100 | 0.535 | 0.021 | 1.06
5403569 | 지상 8층 | 지상 8층 | 5403553 | 444.965 | 0.121241 | 0.00444965 | 0.242483
5403570 | 지상 8층 | 지상 8층 | 5403553 | 1500 | 0.385 | 0.015 | 0.77
5403571 | 지상 8층 | 지상 8층 | 5403553 | 520 | 0.14 | 0.0052 | 0.27
5403575 | 지상 8층 | 지상 8층 | 5403553 | 1500 | 0.385 | 0.015 | 0.77
5403577 | 지상 8층 | 지상 8층 | 5403553 | 445.035 | 0.121259 | 0.00445035 | 0.242517
5403578 | 지상 8층 | 지상 8층 | 5403553 | 2100 | 0.535 | 0.021 | 1.06
5403579 | 지상 8층 | 지상 8층 | 5403553 | 520 | 0.14 | 0.0052 | 0.27
5403582 | 지상 4층 | 지상 4층 | 5403580 | 280.009 | 0.0800022 | 0.00280009 | 0.160004
5403584 | 지상 4층 | 지상 4층 | 5403580 | 2100 | 0.535 | 0.021 | 1.06
5403588 | 지상 4층 | 지상 4층 | 5403580 | 520 | 0.14 | 0.0052 | 0.27
5403590 | 지상 4층 | 지상 4층 | 5403580 | 715 | 0.18875 | 0.00715 | 0.3775
5403594 | 지상 4층 | 지상 4층 | 5403580 | 715 | 0.18875 | 0.00715 | 0.3775
5403596 | 지상 4층 | 지상 4층 | 5403580 | 1495 | 0.38375 | 0.01495 | 0.7675
5403597 | 지상 4층 | 지상 4층 | 5403580 | 2100 | 0.535 | 0.021 | 1.06
5403598 | 지상 4층 | 지상 4층 | 5403580 | 520 | 0.14 | 0.0052 | 0.27
7697132 | 지상 4층 | 지상 4층 | 5403580 | 1495 | 0.38375 | 0.01495 | 0.7675
7697133 | 지상 4층 | 지상 4층 | 5403580 | 280.009 | 0.0800022 | 0.00280009 | 0.160004
5403603 | 지상 5층 | 지상 5층 | 5403601 | 280.009 | 0.0800022 | 0.00280009 | 0.160004
5403605 | 지상 5층 | 지상 5층 | 5403601 | 2100 | 0.535 | 0.021 | 1.06
5403609 | 지상 5층 | 지상 5층 | 5403601 | 520 | 0.14 | 0.0052 | 0.27
5403611 | 지상 5층 | 지상 5층 | 5403601 | 765 | 0.20125 | 0.00765 | 0.4025
5403615 | 지상 5층 | 지상 5층 | 5403601 | 765 | 0.20125 | 0.00765 | 0.4025
5403617 | 지상 5층 | 지상 5층 | 5403601 | 1495 | 0.38375 | 0.01495 | 0.7675
5403618 | 지상 5층 | 지상 5층 | 5403601 | 2100 | 0.535 | 0.021 | 1.06
5403619 | 지상 5층 | 지상 5층 | 5403601 | 520 | 0.14 | 0.0052 | 0.27
7697038 | 지상 5층 | 지상 5층 | 5403601 | 1495 | 0.38375 | 0.01495 | 0.7675
7697039 | 지상 5층 | 지상 5층 | 5403601 | 280.009 | 0.0800022 | 0.00280009 | 0.160004
5403622 | 지상 6층 | 지상 6층 | 5403620 | 280.009 | 0.0800022 | 0.00280009 | 0.160004
5403624 | 지상 6층 | 지상 6층 | 5403620 | 2100 | 0.535 | 0.021 | 1.06
5403628 | 지상 6층 | 지상 6층 | 5403620 | 520 | 0.14 | 0.0052 | 0.27
5403630 | 지상 6층 | 지상 6층 | 5403620 | 759.991 | 0.199998 | 0.00759991 | 0.399996
5403634 | 지상 6층 | 지상 6층 | 5403620 | 759.991 | 0.199998 | 0.00759991 | 0.399996
5403636 | 지상 6층 | 지상 6층 | 5403620 | 1495 | 0.38375 | 0.01495 | 0.7675
5403637 | 지상 6층 | 지상 6층 | 5403620 | 2100 | 0.535 | 0.021 | 1.06
5403638 | 지상 6층 | 지상 6층 | 5403620 | 520 | 0.14 | 0.0052 | 0.27
7696946 | 지상 6층 | 지상 6층 | 5403620 | 1495 | 0.38375 | 0.01495 | 0.7675
7696947 | 지상 6층 | 지상 6층 | 5403620 | 280.009 | 0.0800022 | 0.00280009 | 0.160004
5403641 | 지상 7층 | 지상 7층 | 5403639 | 280.009 | 0.0800022 | 0.00280009 | 0.160004
5403643 | 지상 7층 | 지상 7층 | 5403639 | 2100 | 0.535 | 0.021 | 1.06
5403647 | 지상 7층 | 지상 7층 | 5403639 | 520 | 0.14 | 0.0052 | 0.27
5403649 | 지상 7층 | 지상 7층 | 5403639 | 759.991 | 0.199998 | 0.00759991 | 0.399996
5403653 | 지상 7층 | 지상 7층 | 5403639 | 759.991 | 0.199998 | 0.00759991 | 0.399996
5403655 | 지상 7층 | 지상 7층 | 5403639 | 1495 | 0.38375 | 0.01495 | 0.7675
5403656 | 지상 7층 | 지상 7층 | 5403639 | 2100 | 0.535 | 0.021 | 1.06
5403657 | 지상 7층 | 지상 7층 | 5403639 | 520 | 0.14 | 0.0052 | 0.27
7696898 | 지상 7층 | 지상 7층 | 5403639 | 1495 | 0.38375 | 0.01495 | 0.7675
7696899 | 지상 7층 | 지상 7층 | 5403639 | 280.009 | 0.0800022 | 0.00280009 | 0.160004
5403660 | 지상 8층 | 지상 8층 | 5403658 | 280.009 | 0.0800022 | 0.00280009 | 0.160004
5403662 | 지상 8층 | 지상 8층 | 5403658 | 2100 | 0.535 | 0.021 | 1.06
5403666 | 지상 8층 | 지상 8층 | 5403658 | 520 | 0.14 | 0.0052 | 0.27
5403668 | 지상 8층 | 지상 8층 | 5403658 | 759.991 | 0.199998 | 0.00759991 | 0.399996
5403672 | 지상 8층 | 지상 8층 | 5403658 | 759.991 | 0.199998 | 0.00759991 | 0.399996
5403674 | 지상 8층 | 지상 8층 | 5403658 | 1495 | 0.38375 | 0.01495 | 0.7675
5403675 | 지상 8층 | 지상 8층 | 5403658 | 2100 | 0.535 | 0.021 | 1.06
5403676 | 지상 8층 | 지상 8층 | 5403658 | 520 | 0.14 | 0.0052 | 0.27
7696808 | 지상 8층 | 지상 8층 | 5403658 | 1495 | 0.38375 | 0.01495 | 0.7675
7696809 | 지상 8층 | 지상 8층 | 5403658 | 280.009 | 0.0800022 | 0.00280009 | 0.160004
5403679 | 지상 10층 | 지상 10층 | 5403677 | 2150 | 0.5475 | 0.0215 | 1.095
5403680 | 지상 10층 | 지상 10층 | 5403677 | 2150 | 0.5475 | 0.0215 | 1.095
5403682 | 지상 10층 | 지상 10층 | 5403677 | 1420 | 0.365 | 0.0142 | 0.72
5403686 | 지상 10층 | 지상 10층 | 5403677 | 2100 | 0.535 | 0.021 | 1.06
5403687 | 지상 10층 | 지상 10층 | 5403677 | 2150 | 0.5475 | 0.0215 | 1.095
5403692 | 지상 10층 | 지상 10층 | 5403690 | 450 | 0.1225 | 0.0045 | 0.245
5403698 | 지상 10층 | 지상 10층 | 5403690 | 454.965 | 0.123741 | 0.00454965 | 0.247483
5403700 | 지상 10층 | 지상 10층 | 5403690 | 2100 | 0.535 | 0.021 | 1.06
5403706 | 지상 10층 | 지상 10층 | 5403690 | 454.965 | 0.123741 | 0.00454965 | 0.247483
5403707 | 지상 10층 | 지상 10층 | 5403690 | 1500 | 0.385 | 0.015 | 0.77
5403708 | 지상 10층 | 지상 10층 | 5403690 | 1420 | 0.365 | 0.0142 | 0.72
5403712 | 지상 10층 | 지상 10층 | 5403690 | 1500 | 0.385 | 0.015 | 0.77
5403714 | 지상 10층 | 지상 10층 | 5403690 | 450 | 0.1225 | 0.0045 | 0.245
5403715 | 지상 10층 | 지상 10층 | 5403690 | 2100 | 0.535 | 0.021 | 1.06
5403716 | 지상 10층 | 지상 10층 | 5403690 | 1420 | 0.365 | 0.0142 | 0.72
5403728 | 지상 10층 | 지상 10층 | 5403726 | 280.009 | 0.0800022 | 0.00280009 | 0.160004
5403730 | 지상 10층 | 지상 10층 | 5403726 | 2100 | 0.535 | 0.021 | 1.06
5403734 | 지상 10층 | 지상 10층 | 5403726 | 1420 | 0.365 | 0.0142 | 0.72
5403736 | 지상 10층 | 지상 10층 | 5403726 | 765 | 0.20125 | 0.00765 | 0.4025
5403740 | 지상 10층 | 지상 10층 | 5403726 | 765 | 0.20125 | 0.00765 | 0.4025
5403742 | 지상 10층 | 지상 10층 | 5403726 | 1495 | 0.38375 | 0.01495 | 0.7675
5403743 | 지상 10층 | 지상 10층 | 5403726 | 2100 | 0.535 | 0.021 | 1.06
5403744 | 지상 10층 | 지상 10층 | 5403726 | 1420 | 0.365 | 0.0142 | 0.72
7696651 | 지상 10층 | 지상 10층 | 5403726 | 1495 | 0.38375 | 0.01495 | 0.7675
7696652 | 지상 10층 | 지상 10층 | 5403726 | 280.009 | 0.0800022 | 0.00280009 | 0.160004
5405307 | 지상 3층 | 지상 3층 | 5405305 | 2534.97 | 0.643741 | 0.0253497 | 1.28748
5405308 | 지상 3층 | 지상 3층 | 5405305 | 2265 | 0.57625 | 0.02265 | 1.1525
5405309 | 지상 3층 | 지상 3층 | 5405305 | 2100 | 0.535 | 0.021 | 1.06
5405310 | 지상 3층 | 지상 3층 | 5405305 | 520 | 0.14 | 0.0052 | 0.27
5405313 | 지상 3층 | 지상 3층 | 5405305 | 1500 | 0.385 | 0.015 | 0.77
5405314 | 지상 3층 | 지상 3층 | 5405305 | 2534.97 | 0.643741 | 0.0253497 | 1.28748
5405315 | 지상 3층 | 지상 3층 | 5405305 | 2100 | 0.535 | 0.021 | 1.06
5405318 | 지상 3층 | 지상 3층 | 5405305 | 2265 | 0.57625 | 0.02265 | 1.1525
5405320 | 지상 3층 | 지상 3층 | 5405305 | 2100 | 0.535 | 0.021 | 1.06
5405325 | 지상 3층 | 지상 3층 | 5405305 | 520 | 0.14 | 0.0052 | 0.27
5405326 | 지상 3층 | 지상 3층 | 5405305 | 2100 | 0.535 | 0.021 | 1.06
5405327 | 지상 3층 | 지상 3층 | 5405305 | 2265 | 0.57625 | 0.02265 | 1.1525
5405328 | 지상 3층 | 지상 3층 | 5405305 | 1500 | 0.385 | 0.015 | 0.77
5405329 | 지상 3층 | 지상 3층 | 5405305 | 2534.97 | 0.643741 | 0.0253497 | 1.28748
5405330 | 지상 3층 | 지상 3층 | 5405305 | 520 | 0.14 | 0.0052 | 0.27
5405331 | 지상 3층 | 지상 3층 | 5405305 | 520 | 0.14 | 0.0052 | 0.27
5405788 | 지상 3층 | 지상 3층 | 5405786 | 2100 | 0.535 | 0.021 | 1.07
5405789 | 지상 3층 | 지상 3층 | 5405786 | 2100 | 0.535 | 0.021 | 1.07
5405791 | 지상 3층 | 지상 3층 | 5405786 | 520 | 0.14 | 0.0052 | 0.27
5405795 | 지상 3층 | 지상 3층 | 5405786 | 2100 | 0.535 | 0.021 | 1.06
5405796 | 지상 3층 | 지상 3층 | 5405786 | 2100 | 0.535 | 0.021 | 1.07
5405799 | 지상 3층 | 지상 3층 | 5405797 | 595.035 | 0.158759 | 0.00595035 | 0.317517
5405800 | 지상 3층 | 지상 3층 | 5405797 | 454.965 | 0.123741 | 0.00454965 | 0.247483
5405805 | 지상 3층 | 지상 3층 | 5405797 | 454.965 | 0.123741 | 0.00454965 | 0.247483
5405807 | 지상 3층 | 지상 3층 | 5405797 | 2100 | 0.535 | 0.021 | 1.06
5405813 | 지상 3층 | 지상 3층 | 5405797 | 454.965 | 0.123741 | 0.00454965 | 0.247483
5405814 | 지상 3층 | 지상 3층 | 5405797 | 1500 | 0.385 | 0.015 | 0.77
5405815 | 지상 3층 | 지상 3층 | 5405797 | 520 | 0.14 | 0.0052 | 0.27
5405819 | 지상 3층 | 지상 3층 | 5405797 | 1500 | 0.385 | 0.015 | 0.77
5405820 | 지상 3층 | 지상 3층 | 5405797 | 595.035 | 0.158759 | 0.00595035 | 0.317517
5405821 | 지상 3층 | 지상 3층 | 5405797 | 595.035 | 0.158759 | 0.00595035 | 0.317517
5405822 | 지상 3층 | 지상 3층 | 5405797 | 2100 | 0.535 | 0.021 | 1.06
5405823 | 지상 3층 | 지상 3층 | 5405797 | 520 | 0.14 | 0.0052 | 0.27
5818110 | 지상 9층 | 지상 9층 | 5818108 | 892.184 | 0.233046 | 0.00892184 | 0.466092
5818111 | 지상 9층 | 지상 9층 | 5818108 | 912.816 | 0.238204 | 0.00912816 | 0.476408
5818116 | 지상 9층 | 지상 9층 | 5818108 | 912.816 | 0.238204 | 0.00912816 | 0.476408
5818120 | 지상 9층 | 지상 9층 | 5818108 | 912.816 | 0.238204 | 0.00912816 | 0.476408
5818125 | 지상 9층 | 지상 9층 | 5818108 | 912.816 | 0.238204 | 0.00912816 | 0.476408
5818126 | 지상 9층 | 지상 9층 | 5818108 | 970 | 0.2525 | 0.0097 | 0.495
5818127 | 지상 9층 | 지상 9층 | 5818108 | 945 | 0.24625 | 0.00945 | 0.4925
5818128 | 지상 9층 | 지상 9층 | 5818108 | 945 | 0.24625 | 0.00945 | 0.4925
5818129 | 지상 9층 | 지상 9층 | 5818108 | 300 | 0.085 | 0.003 | 0.16
5818130 | 지상 9층 | 지상 9층 | 5818108 | 600 | 0.16 | 0.006 | 0.3
5818131 | 지상 9층 | 지상 9층 | 5818108 | 1600 | 0.41 | 0.016 | 0.81
5818136 | 지상 9층 | 지상 9층 | 5818108 | 940 | 0.245 | 0.0094 | 0.48
5818137 | 지상 9층 | 지상 9층 | 5818108 | 940 | 0.245 | 0.0094 | 0.48
5818138 | 지상 9층 | 지상 9층 | 5818108 | 915 | 0.23875 | 0.00915 | 0.4775
5818139 | 지상 9층 | 지상 9층 | 5818108 | 915 | 0.23875 | 0.00915 | 0.4775
5818140 | 지상 9층 | 지상 9층 | 5818108 | 300 | 0.085 | 0.003 | 0.16
5818141 | 지상 9층 | 지상 9층 | 5818108 | 600 | 0.16 | 0.006 | 0.3
5818142 | 지상 9층 | 지상 9층 | 5818108 | 1600 | 0.41 | 0.016 | 0.81
5818147 | 지상 9층 | 지상 9층 | 5818108 | 940 | 0.245 | 0.0094 | 0.48
5818148 | 지상 9층 | 지상 9층 | 5818108 | 940 | 0.245 | 0.0094 | 0.48
5818149 | 지상 9층 | 지상 9층 | 5818108 | 915 | 0.23875 | 0.00915 | 0.4775
5818150 | 지상 9층 | 지상 9층 | 5818108 | 915 | 0.23875 | 0.00915 | 0.4775
5818151 | 지상 9층 | 지상 9층 | 5818108 | 300 | 0.085 | 0.003 | 0.16
5818152 | 지상 9층 | 지상 9층 | 5818108 | 600 | 0.16 | 0.006 | 0.3
5818153 | 지상 9층 | 지상 9층 | 5818108 | 1600 | 0.41 | 0.016 | 0.81
5818158 | 지상 9층 | 지상 9층 | 5818108 | 940 | 0.245 | 0.0094 | 0.48
5818159 | 지상 9층 | 지상 9층 | 5818108 | 940 | 0.245 | 0.0094 | 0.48
5818160 | 지상 9층 | 지상 9층 | 5818108 | 915 | 0.23875 | 0.00915 | 0.4775
5818161 | 지상 9층 | 지상 9층 | 5818108 | 915 | 0.23875 | 0.00915 | 0.4775
5818162 | 지상 9층 | 지상 9층 | 5818108 | 300 | 0.085 | 0.003 | 0.16
5818163 | 지상 9층 | 지상 9층 | 5818108 | 600 | 0.16 | 0.006 | 0.3
5818164 | 지상 9층 | 지상 9층 | 5818108 | 1600 | 0.41 | 0.016 | 0.81
5818169 | 지상 9층 | 지상 9층 | 5818108 | 940 | 0.245 | 0.0094 | 0.48
5818170 | 지상 9층 | 지상 9층 | 5818108 | 940 | 0.245 | 0.0094 | 0.48
5818171 | 지상 9층 | 지상 9층 | 5818108 | 915 | 0.23875 | 0.00915 | 0.4775
5818172 | 지상 9층 | 지상 9층 | 5818108 | 915 | 0.23875 | 0.00915 | 0.4775
5818173 | 지상 9층 | 지상 9층 | 5818108 | 300 | 0.085 | 0.003 | 0.16
5818174 | 지상 9층 | 지상 9층 | 5818108 | 600 | 0.16 | 0.006 | 0.3
5818175 | 지상 9층 | 지상 9층 | 5818108 | 1600 | 0.41 | 0.016 | 0.81
5818180 | 지상 9층 | 지상 9층 | 5818108 | 940 | 0.245 | 0.0094 | 0.48
5818181 | 지상 9층 | 지상 9층 | 5818108 | 940 | 0.245 | 0.0094 | 0.48
5818182 | 지상 9층 | 지상 9층 | 5818108 | 915 | 0.23875 | 0.00915 | 0.4775
5818183 | 지상 9층 | 지상 9층 | 5818108 | 915 | 0.23875 | 0.00915 | 0.4775
5818184 | 지상 9층 | 지상 9층 | 5818108 | 300 | 0.085 | 0.003 | 0.16
5818185 | 지상 9층 | 지상 9층 | 5818108 | 600 | 0.16 | 0.006 | 0.3
5818186 | 지상 9층 | 지상 9층 | 5818108 | 1600 | 0.41 | 0.016 | 0.81
5818191 | 지상 9층 | 지상 9층 | 5818108 | 970 | 0.2525 | 0.0097 | 0.495
5818192 | 지상 9층 | 지상 9층 | 5818108 | 1010 | 0.2625 | 0.0101 | 0.525
5818193 | 지상 9층 | 지상 9층 | 5818108 | 1010 | 0.2625 | 0.0101 | 0.525
5818194 | 지상 9층 | 지상 9층 | 5818108 | 1010 | 0.2625 | 0.0101 | 0.525
5818195 | 지상 9층 | 지상 9층 | 5818108 | 300 | 0.085 | 0.003 | 0.16
5818196 | 지상 9층 | 지상 9층 | 5818108 | 600 | 0.16 | 0.006 | 0.3
5818197 | 지상 9층 | 지상 9층 | 5818108 | 1600 | 0.41 | 0.016 | 0.81
5818202 | 지상 9층 | 지상 9층 | 5818108 | 1010 | 0.2625 | 0.0101 | 0.525
5818203 | 지상 9층 | 지상 9층 | 5818108 | 1080 | 0.28 | 0.0108 | 0.55
5818204 | 지상 9층 | 지상 9층 | 5818108 | 1055 | 0.27375 | 0.01055 | 0.5475
5818205 | 지상 9층 | 지상 9층 | 5818108 | 1055 | 0.27375 | 0.01055 | 0.5475
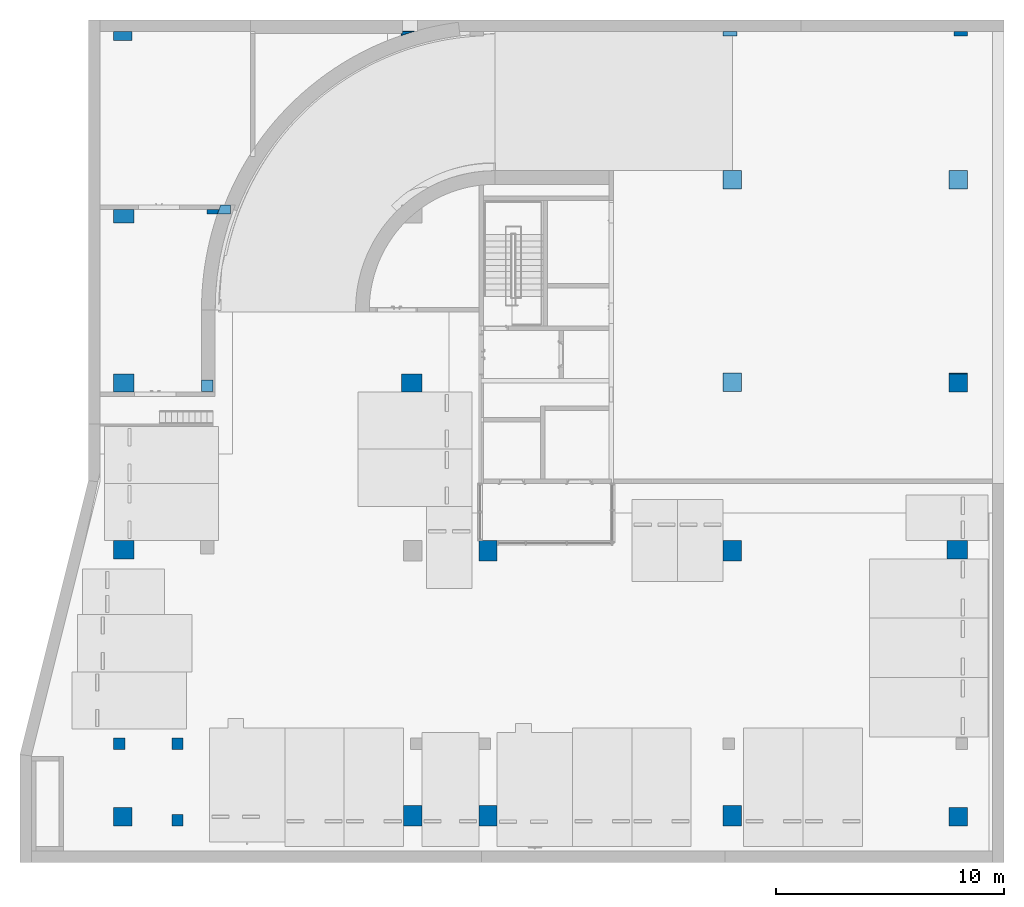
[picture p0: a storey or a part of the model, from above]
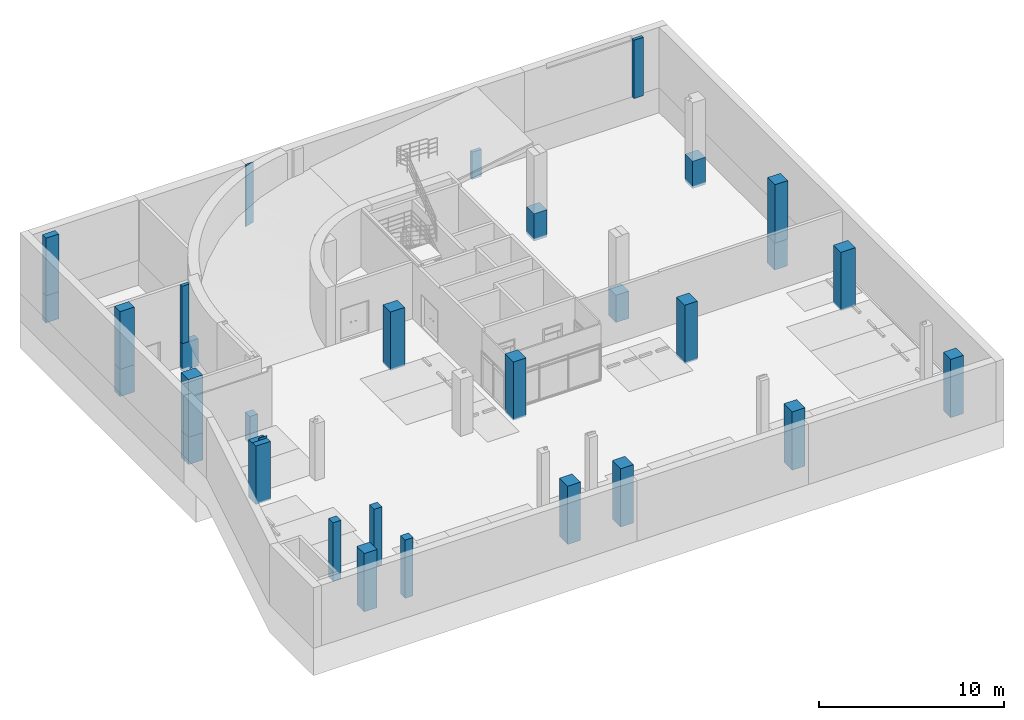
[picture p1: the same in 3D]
Properties of the parts of a building model (IFC2X3), part 21 of 39

# IfcMember: 직사각형 멀리언:CW200-직사각형 멀리언 50x200mm (8700)
Name (직사각형 멀리언:CW200-직사각형 멀리언 50x200mm:...) | In | 레벨 | 호스트 ID | 길이 (mm) = Span (mm) | 면적 (m2) = CrossSectionArea (m2) | 체적 (m3) = NetVolume (m3) | NetSurfaceArea (m2)
5818206 | 지상 9층 | 지상 9층 | 5818108 | 300 | 0.085 | 0.003 | 0.16
5818207 | 지상 9층 | 지상 9층 | 5818108 | 600 | 0.16 | 0.006 | 0.3
5818208 | 지상 9층 | 지상 9층 | 5818108 | 1600 | 0.41 | 0.016 | 0.81
5818213 | 지상 9층 | 지상 9층 | 5818108 | 1110 | 0.2875 | 0.0111 | 0.565
5818214 | 지상 9층 | 지상 9층 | 5818108 | 1010 | 0.2625 | 0.0101 | 0.525
5818215 | 지상 9층 | 지상 9층 | 5818108 | 1010 | 0.2625 | 0.0101 | 0.525
5818216 | 지상 9층 | 지상 9층 | 5818108 | 1010 | 0.2625 | 0.0101 | 0.525
5818217 | 지상 9층 | 지상 9층 | 5818108 | 300 | 0.085 | 0.003 | 0.16
5818218 | 지상 9층 | 지상 9층 | 5818108 | 600 | 0.16 | 0.006 | 0.3
5818219 | 지상 9층 | 지상 9층 | 5818108 | 1600 | 0.41 | 0.016 | 0.81
5818224 | 지상 9층 | 지상 9층 | 5818108 | 1010 | 0.2625 | 0.0101 | 0.525
5818225 | 지상 9층 | 지상 9층 | 5818108 | 940 | 0.245 | 0.0094 | 0.48
5818226 | 지상 9층 | 지상 9층 | 5818108 | 915 | 0.23875 | 0.00915 | 0.4775
5818227 | 지상 9층 | 지상 9층 | 5818108 | 915 | 0.23875 | 0.00915 | 0.4775
5818228 | 지상 9층 | 지상 9층 | 5818108 | 300 | 0.085 | 0.003 | 0.16
5818229 | 지상 9층 | 지상 9층 | 5818108 | 600 | 0.16 | 0.006 | 0.3
5818230 | 지상 9층 | 지상 9층 | 5818108 | 1600 | 0.41 | 0.016 | 0.81
5818235 | 지상 9층 | 지상 9층 | 5818108 | 940 | 0.245 | 0.0094 | 0.48
5818236 | 지상 9층 | 지상 9층 | 5818108 | 940 | 0.245 | 0.0094 | 0.48
5818237 | 지상 9층 | 지상 9층 | 5818108 | 915 | 0.23875 | 0.00915 | 0.4775
5818238 | 지상 9층 | 지상 9층 | 5818108 | 915 | 0.23875 | 0.00915 | 0.4775
5818239 | 지상 9층 | 지상 9층 | 5818108 | 300 | 0.085 | 0.003 | 0.16
5818240 | 지상 9층 | 지상 9층 | 5818108 | 600 | 0.16 | 0.006 | 0.3
5818241 | 지상 9층 | 지상 9층 | 5818108 | 1600 | 0.41 | 0.016 | 0.81
5818246 | 지상 9층 | 지상 9층 | 5818108 | 940 | 0.245 | 0.0094 | 0.48
5818247 | 지상 9층 | 지상 9층 | 5818108 | 940 | 0.245 | 0.0094 | 0.48
5818248 | 지상 9층 | 지상 9층 | 5818108 | 915 | 0.23875 | 0.00915 | 0.4775
5818249 | 지상 9층 | 지상 9층 | 5818108 | 915 | 0.23875 | 0.00915 | 0.4775
5818250 | 지상 9층 | 지상 9층 | 5818108 | 300 | 0.085 | 0.003 | 0.16
5818251 | 지상 9층 | 지상 9층 | 5818108 | 600 | 0.16 | 0.006 | 0.3
5818252 | 지상 9층 | 지상 9층 | 5818108 | 1600 | 0.41 | 0.016 | 0.81
5818257 | 지상 9층 | 지상 9층 | 5818108 | 940 | 0.245 | 0.0094 | 0.48
5818258 | 지상 9층 | 지상 9층 | 5818108 | 940 | 0.245 | 0.0094 | 0.48
5818259 | 지상 9층 | 지상 9층 | 5818108 | 915 | 0.23875 | 0.00915 | 0.4775
5818260 | 지상 9층 | 지상 9층 | 5818108 | 915 | 0.23875 | 0.00915 | 0.4775
5818261 | 지상 9층 | 지상 9층 | 5818108 | 300 | 0.085 | 0.003 | 0.16
5818262 | 지상 9층 | 지상 9층 | 5818108 | 600 | 0.16 | 0.006 | 0.3
5818263 | 지상 9층 | 지상 9층 | 5818108 | 1600 | 0.41 | 0.016 | 0.81
5818268 | 지상 9층 | 지상 9층 | 5818108 | 940 | 0.245 | 0.0094 | 0.48
5818269 | 지상 9층 | 지상 9층 | 5818108 | 940 | 0.245 | 0.0094 | 0.48
5818270 | 지상 9층 | 지상 9층 | 5818108 | 915 | 0.23875 | 0.00915 | 0.4775
5818271 | 지상 9층 | 지상 9층 | 5818108 | 915 | 0.23875 | 0.00915 | 0.4775
5818272 | 지상 9층 | 지상 9층 | 5818108 | 300 | 0.085 | 0.003 | 0.16
5818273 | 지상 9층 | 지상 9층 | 5818108 | 600 | 0.16 | 0.006 | 0.3
5818274 | 지상 9층 | 지상 9층 | 5818108 | 1600 | 0.41 | 0.016 | 0.81
5818279 | 지상 9층 | 지상 9층 | 5818108 | 935 | 0.24375 | 0.00935 | 0.4775
5818280 | 지상 9층 | 지상 9층 | 5818108 | 1010 | 0.2625 | 0.0101 | 0.525
5818281 | 지상 9층 | 지상 9층 | 5818108 | 1010 | 0.2625 | 0.0101 | 0.525
5818282 | 지상 9층 | 지상 9층 | 5818108 | 1010 | 0.2625 | 0.0101 | 0.525
5818283 | 지상 9층 | 지상 9층 | 5818108 | 300 | 0.085 | 0.003 | 0.16
5818284 | 지상 9층 | 지상 9층 | 5818108 | 600 | 0.16 | 0.006 | 0.3
5818285 | 지상 9층 | 지상 9층 | 5818108 | 1600 | 0.41 | 0.016 | 0.81
5818290 | 지상 9층 | 지상 9층 | 5818108 | 1010 | 0.2625 | 0.0101 | 0.525
5818291 | 지상 9층 | 지상 9층 | 5818108 | 995 | 0.25875 | 0.00995 | 0.5075
5818292 | 지상 9층 | 지상 9층 | 5818108 | 970 | 0.2525 | 0.0097 | 0.505
5818293 | 지상 9층 | 지상 9층 | 5818108 | 970 | 0.2525 | 0.0097 | 0.505
5818294 | 지상 9층 | 지상 9층 | 5818108 | 300 | 0.085 | 0.003 | 0.16
5818295 | 지상 9층 | 지상 9층 | 5818108 | 600 | 0.16 | 0.006 | 0.3
5818296 | 지상 9층 | 지상 9층 | 5818108 | 1600 | 0.41 | 0.016 | 0.81
5818301 | 지상 9층 | 지상 9층 | 5818108 | 940 | 0.245 | 0.0094 | 0.48
5818302 | 지상 9층 | 지상 9층 | 5818108 | 940 | 0.245 | 0.0094 | 0.48
5818303 | 지상 9층 | 지상 9층 | 5818108 | 915 | 0.23875 | 0.00915 | 0.4775
5818304 | 지상 9층 | 지상 9층 | 5818108 | 915 | 0.23875 | 0.00915 | 0.4775
5818305 | 지상 9층 | 지상 9층 | 5818108 | 300 | 0.085 | 0.003 | 0.16
5818306 | 지상 9층 | 지상 9층 | 5818108 | 600 | 0.16 | 0.006 | 0.3
5818307 | 지상 9층 | 지상 9층 | 5818108 | 1600 | 0.41 | 0.016 | 0.81
5818312 | 지상 9층 | 지상 9층 | 5818108 | 940 | 0.245 | 0.0094 | 0.48
5818313 | 지상 9층 | 지상 9층 | 5818108 | 940 | 0.245 | 0.0094 | 0.48
5818314 | 지상 9층 | 지상 9층 | 5818108 | 915 | 0.23875 | 0.00915 | 0.4775
5818315 | 지상 9층 | 지상 9층 | 5818108 | 915 | 0.23875 | 0.00915 | 0.4775
5818316 | 지상 9층 | 지상 9층 | 5818108 | 300 | 0.085 | 0.003 | 0.16
5818317 | 지상 9층 | 지상 9층 | 5818108 | 600 | 0.16 | 0.006 | 0.3
5818318 | 지상 9층 | 지상 9층 | 5818108 | 1600 | 0.41 | 0.016 | 0.81
5818323 | 지상 9층 | 지상 9층 | 5818108 | 940 | 0.245 | 0.0094 | 0.48
5818324 | 지상 9층 | 지상 9층 | 5818108 | 940 | 0.245 | 0.0094 | 0.48
5818325 | 지상 9층 | 지상 9층 | 5818108 | 915 | 0.23875 | 0.00915 | 0.4775
5818326 | 지상 9층 | 지상 9층 | 5818108 | 915 | 0.23875 | 0.00915 | 0.4775
5818327 | 지상 9층 | 지상 9층 | 5818108 | 300 | 0.085 | 0.003 | 0.16
5818328 | 지상 9층 | 지상 9층 | 5818108 | 600 | 0.16 | 0.006 | 0.3
5818329 | 지상 9층 | 지상 9층 | 5818108 | 1600 | 0.41 | 0.016 | 0.81
5818334 | 지상 9층 | 지상 9층 | 5818108 | 940 | 0.245 | 0.0094 | 0.48
5818335 | 지상 9층 | 지상 9층 | 5818108 | 1015 | 0.26375 | 0.01015 | 0.5275
5818336 | 지상 9층 | 지상 9층 | 5818108 | 1015 | 0.26375 | 0.01015 | 0.5275
5818337 | 지상 9층 | 지상 9층 | 5818108 | 1015 | 0.26375 | 0.01015 | 0.5275
5818338 | 지상 9층 | 지상 9층 | 5818108 | 300 | 0.085 | 0.003 | 0.16
5818339 | 지상 9층 | 지상 9층 | 5818108 | 600 | 0.16 | 0.006 | 0.3
5818340 | 지상 9층 | 지상 9층 | 5818108 | 1600 | 0.41 | 0.016 | 0.81
5818345 | 지상 9층 | 지상 9층 | 5818108 | 1015 | 0.26375 | 0.01015 | 0.5275
5818346 | 지상 9층 | 지상 9층 | 5818108 | 892.184 | 0.233046 | 0.00892184 | 0.466092
5818347 | 지상 9층 | 지상 9층 | 5818108 | 892.184 | 0.233046 | 0.00892184 | 0.466092
5818348 | 지상 9층 | 지상 9층 | 5818108 | 892.184 | 0.233046 | 0.00892184 | 0.466092
5818349 | 지상 9층 | 지상 9층 | 5818108 | 300 | 0.085 | 0.003 | 0.16
5818350 | 지상 9층 | 지상 9층 | 5818108 | 600 | 0.16 | 0.006 | 0.3
5818351 | 지상 9층 | 지상 9층 | 5818108 | 1600 | 0.41 | 0.016 | 0.81
5818356 | 지상 9층 | 지상 9층 | 5818108 | 970 | 0.2525 | 0.0097 | 0.495
5818357 | 지상 9층 | 지상 9층 | 5818108 | 940 | 0.245 | 0.0094 | 0.48
5818358 | 지상 9층 | 지상 9층 | 5818108 | 915 | 0.23875 | 0.00915 | 0.4775
5818359 | 지상 9층 | 지상 9층 | 5818108 | 915 | 0.23875 | 0.00915 | 0.4775
5818360 | 지상 9층 | 지상 9층 | 5818108 | 650 | 0.1725 | 0.0065 | 0.345
5818365 | 지상 9층 | 지상 9층 | 5818108 | 940 | 0.245 | 0.0094 | 0.48
5818366 | 지상 9층 | 지상 9층 | 5818108 | 915 | 0.23875 | 0.00915 | 0.4775
5818367 | 지상 9층 | 지상 9층 | 5818108 | 915 | 0.23875 | 0.00915 | 0.4775
5818368 | 지상 9층 | 지상 9층 | 5818108 | 940 | 0.245 | 0.0094 | 0.48
5818369 | 지상 9층 | 지상 9층 | 5818108 | 650 | 0.1725 | 0.0065 | 0.345
5818374 | 지상 9층 | 지상 9층 | 5818108 | 940 | 0.245 | 0.0094 | 0.48
5818375 | 지상 9층 | 지상 9층 | 5818108 | 915 | 0.23875 | 0.00915 | 0.4775
5818376 | 지상 9층 | 지상 9층 | 5818108 | 915 | 0.23875 | 0.00915 | 0.4775
5818377 | 지상 9층 | 지상 9층 | 5818108 | 940 | 0.245 | 0.0094 | 0.48
5818378 | 지상 9층 | 지상 9층 | 5818108 | 650 | 0.1725 | 0.0065 | 0.345
5818383 | 지상 9층 | 지상 9층 | 5818108 | 940 | 0.245 | 0.0094 | 0.48
5818384 | 지상 9층 | 지상 9층 | 5818108 | 915 | 0.23875 | 0.00915 | 0.4775
5818385 | 지상 9층 | 지상 9층 | 5818108 | 915 | 0.23875 | 0.00915 | 0.4775
5818386 | 지상 9층 | 지상 9층 | 5818108 | 940 | 0.245 | 0.0094 | 0.48
5818387 | 지상 9층 | 지상 9층 | 5818108 | 650 | 0.1725 | 0.0065 | 0.345
5818392 | 지상 9층 | 지상 9층 | 5818108 | 940 | 0.245 | 0.0094 | 0.48
5818393 | 지상 9층 | 지상 9층 | 5818108 | 915 | 0.23875 | 0.00915 | 0.4775
5818394 | 지상 9층 | 지상 9층 | 5818108 | 915 | 0.23875 | 0.00915 | 0.4775
5818395 | 지상 9층 | 지상 9층 | 5818108 | 940 | 0.245 | 0.0094 | 0.48
5818396 | 지상 9층 | 지상 9층 | 5818108 | 650 | 0.1725 | 0.0065 | 0.345
5818401 | 지상 9층 | 지상 9층 | 5818108 | 970 | 0.2525 | 0.0097 | 0.495
5818402 | 지상 9층 | 지상 9층 | 5818108 | 945 | 0.24625 | 0.00945 | 0.4925
5818403 | 지상 9층 | 지상 9층 | 5818108 | 945 | 0.24625 | 0.00945 | 0.4925
5818404 | 지상 9층 | 지상 9층 | 5818108 | 940 | 0.245 | 0.0094 | 0.48
5818405 | 지상 9층 | 지상 9층 | 5818108 | 650 | 0.1725 | 0.0065 | 0.345
5818410 | 지상 9층 | 지상 9층 | 5818108 | 1110 | 0.2875 | 0.0111 | 0.565
5818411 | 지상 9층 | 지상 9층 | 5818108 | 1085.02 | 0.281254 | 0.0108502 | 0.562508
5818412 | 지상 9층 | 지상 9층 | 5818108 | 1085.02 | 0.281254 | 0.0108502 | 0.562508
5818413 | 지상 9층 | 지상 9층 | 5818108 | 1080 | 0.28 | 0.0108 | 0.55
5818414 | 지상 9층 | 지상 9층 | 5818108 | 650 | 0.1725 | 0.0065 | 0.345
5818419 | 지상 9층 | 지상 9층 | 5818108 | 940 | 0.245 | 0.0094 | 0.48
5818420 | 지상 9층 | 지상 9층 | 5818108 | 915 | 0.23875 | 0.00915 | 0.4775
5818421 | 지상 9층 | 지상 9층 | 5818108 | 915 | 0.23875 | 0.00915 | 0.4775
5818422 | 지상 9층 | 지상 9층 | 5818108 | 940 | 0.245 | 0.0094 | 0.48
5818423 | 지상 9층 | 지상 9층 | 5818108 | 650 | 0.1725 | 0.0065 | 0.345
5818428 | 지상 9층 | 지상 9층 | 5818108 | 940 | 0.245 | 0.0094 | 0.48
5818429 | 지상 9층 | 지상 9층 | 5818108 | 915 | 0.23875 | 0.00915 | 0.4775
5818430 | 지상 9층 | 지상 9층 | 5818108 | 915 | 0.23875 | 0.00915 | 0.4775
5818431 | 지상 9층 | 지상 9층 | 5818108 | 940 | 0.245 | 0.0094 | 0.48
5818432 | 지상 9층 | 지상 9층 | 5818108 | 650 | 0.1725 | 0.0065 | 0.345
5818437 | 지상 9층 | 지상 9층 | 5818108 | 940 | 0.245 | 0.0094 | 0.48
5818438 | 지상 9층 | 지상 9층 | 5818108 | 915 | 0.23875 | 0.00915 | 0.4775
5818439 | 지상 9층 | 지상 9층 | 5818108 | 915 | 0.23875 | 0.00915 | 0.4775
5818440 | 지상 9층 | 지상 9층 | 5818108 | 940 | 0.245 | 0.0094 | 0.48
5818441 | 지상 9층 | 지상 9층 | 5818108 | 650 | 0.1725 | 0.0065 | 0.345
5818446 | 지상 9층 | 지상 9층 | 5818108 | 940 | 0.245 | 0.0094 | 0.48
5818447 | 지상 9층 | 지상 9층 | 5818108 | 915 | 0.23875 | 0.00915 | 0.4775
5818448 | 지상 9층 | 지상 9층 | 5818108 | 915 | 0.23875 | 0.00915 | 0.4775
5818449 | 지상 9층 | 지상 9층 | 5818108 | 940 | 0.245 | 0.0094 | 0.48
5818450 | 지상 9층 | 지상 9층 | 5818108 | 650 | 0.1725 | 0.0065 | 0.345
5818455 | 지상 9층 | 지상 9층 | 5818108 | 935 | 0.24375 | 0.00935 | 0.4775
5818456 | 지상 9층 | 지상 9층 | 5818108 | 910 | 0.2375 | 0.0091 | 0.475
5818457 | 지상 9층 | 지상 9층 | 5818108 | 910 | 0.2375 | 0.0091 | 0.475
5818458 | 지상 9층 | 지상 9층 | 5818108 | 940 | 0.245 | 0.0094 | 0.48
5818459 | 지상 9층 | 지상 9층 | 5818108 | 650 | 0.1725 | 0.0065 | 0.345
5818464 | 지상 9층 | 지상 9층 | 5818108 | 940 | 0.245 | 0.0094 | 0.48
5818465 | 지상 9층 | 지상 9층 | 5818108 | 915 | 0.23875 | 0.00915 | 0.4775
5818466 | 지상 9층 | 지상 9층 | 5818108 | 915 | 0.23875 | 0.00915 | 0.4775
5818467 | 지상 9층 | 지상 9층 | 5818108 | 995 | 0.25875 | 0.00995 | 0.5075
5818468 | 지상 9층 | 지상 9층 | 5818108 | 650 | 0.1725 | 0.0065 | 0.345
5818473 | 지상 9층 | 지상 9층 | 5818108 | 940 | 0.245 | 0.0094 | 0.48
5818474 | 지상 9층 | 지상 9층 | 5818108 | 915 | 0.23875 | 0.00915 | 0.4775
5818475 | 지상 9층 | 지상 9층 | 5818108 | 915 | 0.23875 | 0.00915 | 0.4775
5818476 | 지상 9층 | 지상 9층 | 5818108 | 940 | 0.245 | 0.0094 | 0.48
5818477 | 지상 9층 | 지상 9층 | 5818108 | 650 | 0.1725 | 0.0065 | 0.345
5818482 | 지상 9층 | 지상 9층 | 5818108 | 940 | 0.245 | 0.0094 | 0.48
5818483 | 지상 9층 | 지상 9층 | 5818108 | 915 | 0.23875 | 0.00915 | 0.4775
5818484 | 지상 9층 | 지상 9층 | 5818108 | 915 | 0.23875 | 0.00915 | 0.4775
5818485 | 지상 9층 | 지상 9층 | 5818108 | 940 | 0.245 | 0.0094 | 0.48
5818486 | 지상 9층 | 지상 9층 | 5818108 | 650 | 0.1725 | 0.0065 | 0.345
5818491 | 지상 9층 | 지상 9층 | 5818108 | 940 | 0.245 | 0.0094 | 0.48
5818492 | 지상 9층 | 지상 9층 | 5818108 | 915 | 0.23875 | 0.00915 | 0.4775
5818493 | 지상 9층 | 지상 9층 | 5818108 | 915 | 0.23875 | 0.00915 | 0.4775
5818494 | 지상 9층 | 지상 9층 | 5818108 | 940 | 0.245 | 0.0094 | 0.48
5818495 | 지상 9층 | 지상 9층 | 5818108 | 650 | 0.1725 | 0.0065 | 0.345
5818683 | 지상 9층 | 지상 9층 | 5818681 | 912.5 | 0.238125 | 0.009125 | 0.47625
5818684 | 지상 9층 | 지상 9층 | 5818681 | 178.395 | 0.0545986 | 0.00178395 | 0.109197
5818686 | 지상 9층 | 지상 9층 | 5818681 | 1600 | 0.41 | 0.016 | 0.81
5818690 | 지상 9층 | 지상 9층 | 5818681 | 300 | 0.085 | 0.003 | 0.16
5818691 | 지상 9층 | 지상 9층 | 5818681 | 178.395 | 0.0545986 | 0.00178395 | 0.109197
5818695 | 지상 9층 | 지상 9층 | 5818681 | 600 | 0.16 | 0.006 | 0.3
5818696 | 지상 9층 | 지상 9층 | 5818681 | 178.395 | 0.0545986 | 0.00178395 | 0.109197
5818701 | 지상 9층 | 지상 9층 | 5818681 | 178.395 | 0.0545986 | 0.00178395 | 0.109197
5818702 | 지상 9층 | 지상 9층 | 5818681 | 828.5 | 0.217125 | 0.008285 | 0.42425
5818703 | 지상 9층 | 지상 9층 | 5818681 | 803.5 | 0.210875 | 0.008035 | 0.42175
5818704 | 지상 9층 | 지상 9층 | 5818681 | 803.5 | 0.210875 | 0.008035 | 0.42175
5818705 | 지상 9층 | 지상 9층 | 5818681 | 300 | 0.085 | 0.003 | 0.16
5818706 | 지상 9층 | 지상 9층 | 5818681 | 600 | 0.16 | 0.006 | 0.3
5818707 | 지상 9층 | 지상 9층 | 5818681 | 1600 | 0.41 | 0.016 | 0.81
5818712 | 지상 9층 | 지상 9층 | 5818681 | 828.5 | 0.217125 | 0.008285 | 0.42425
5818713 | 지상 9층 | 지상 9층 | 5818681 | 828.5 | 0.217125 | 0.008285 | 0.42425
5818714 | 지상 9층 | 지상 9층 | 5818681 | 803.5 | 0.210875 | 0.008035 | 0.42175
5818715 | 지상 9층 | 지상 9층 | 5818681 | 803.5 | 0.210875 | 0.008035 | 0.42175
5818716 | 지상 9층 | 지상 9층 | 5818681 | 300 | 0.085 | 0.003 | 0.16
5818717 | 지상 9층 | 지상 9층 | 5818681 | 600 | 0.16 | 0.006 | 0.3
5818718 | 지상 9층 | 지상 9층 | 5818681 | 1600 | 0.41 | 0.016 | 0.81
5818723 | 지상 9층 | 지상 9층 | 5818681 | 828.5 | 0.217125 | 0.008285 | 0.42425
5818724 | 지상 9층 | 지상 9층 | 5818681 | 828.5 | 0.217125 | 0.008285 | 0.42425
5818725 | 지상 9층 | 지상 9층 | 5818681 | 803.5 | 0.210875 | 0.008035 | 0.42175
5818726 | 지상 9층 | 지상 9층 | 5818681 | 803.5 | 0.210875 | 0.008035 | 0.42175
5818727 | 지상 9층 | 지상 9층 | 5818681 | 300 | 0.085 | 0.003 | 0.16
5818728 | 지상 9층 | 지상 9층 | 5818681 | 600 | 0.16 | 0.006 | 0.3
5818729 | 지상 9층 | 지상 9층 | 5818681 | 1600 | 0.41 | 0.016 | 0.81
5818734 | 지상 9층 | 지상 9층 | 5818681 | 828.5 | 0.217125 | 0.008285 | 0.42425
5818735 | 지상 9층 | 지상 9층 | 5818681 | 828.5 | 0.217125 | 0.008285 | 0.42425
5818736 | 지상 9층 | 지상 9층 | 5818681 | 803.5 | 0.210875 | 0.008035 | 0.42175
5818737 | 지상 9층 | 지상 9층 | 5818681 | 803.5 | 0.210875 | 0.008035 | 0.42175
5818738 | 지상 9층 | 지상 9층 | 5818681 | 300 | 0.085 | 0.003 | 0.16
5818739 | 지상 9층 | 지상 9층 | 5818681 | 600 | 0.16 | 0.006 | 0.3
5818740 | 지상 9층 | 지상 9층 | 5818681 | 1600 | 0.41 | 0.016 | 0.81
5818745 | 지상 9층 | 지상 9층 | 5818681 | 828.5 | 0.217125 | 0.008285 | 0.42425
5818746 | 지상 9층 | 지상 9층 | 5818681 | 1120 | 0.29 | 0.0112 | 0.58
5818747 | 지상 9층 | 지상 9층 | 5818681 | 1120 | 0.29 | 0.0112 | 0.58
5818748 | 지상 9층 | 지상 9층 | 5818681 | 1120 | 0.29 | 0.0112 | 0.58
5818749 | 지상 9층 | 지상 9층 | 5818681 | 300 | 0.085 | 0.003 | 0.16
5818750 | 지상 9층 | 지상 9층 | 5818681 | 600 | 0.16 | 0.006 | 0.3
5818751 | 지상 9층 | 지상 9층 | 5818681 | 1600 | 0.41 | 0.016 | 0.81
5818756 | 지상 9층 | 지상 9층 | 5818681 | 1120 | 0.29 | 0.0112 | 0.58
5818757 | 지상 9층 | 지상 9층 | 5818681 | 754 | 0.1985 | 0.00754 | 0.387
5818758 | 지상 9층 | 지상 9층 | 5818681 | 729 | 0.19225 | 0.00729 | 0.3845
5818759 | 지상 9층 | 지상 9층 | 5818681 | 729 | 0.19225 | 0.00729 | 0.3845
5818760 | 지상 9층 | 지상 9층 | 5818681 | 300 | 0.085 | 0.003 | 0.16
5818761 | 지상 9층 | 지상 9층 | 5818681 | 600 | 0.16 | 0.006 | 0.3
5818762 | 지상 9층 | 지상 9층 | 5818681 | 1600 | 0.41 | 0.016 | 0.81
5818767 | 지상 9층 | 지상 9층 | 5818681 | 754 | 0.1985 | 0.00754 | 0.387
5818768 | 지상 9층 | 지상 9층 | 5818681 | 754 | 0.1985 | 0.00754 | 0.387
5818769 | 지상 9층 | 지상 9층 | 5818681 | 729 | 0.19225 | 0.00729 | 0.3845
5818770 | 지상 9층 | 지상 9층 | 5818681 | 729 | 0.19225 | 0.00729 | 0.3845
5818771 | 지상 9층 | 지상 9층 | 5818681 | 300 | 0.085 | 0.003 | 0.16
5818772 | 지상 9층 | 지상 9층 | 5818681 | 600 | 0.16 | 0.006 | 0.3
5818773 | 지상 9층 | 지상 9층 | 5818681 | 1600 | 0.41 | 0.016 | 0.81
5818778 | 지상 9층 | 지상 9층 | 5818681 | 754 | 0.1985 | 0.00754 | 0.387
5818779 | 지상 9층 | 지상 9층 | 5818681 | 754 | 0.1985 | 0.00754 | 0.387
5818780 | 지상 9층 | 지상 9층 | 5818681 | 729 | 0.19225 | 0.00729 | 0.3845
5818781 | 지상 9층 | 지상 9층 | 5818681 | 729 | 0.19225 | 0.00729 | 0.3845
5818782 | 지상 9층 | 지상 9층 | 5818681 | 300 | 0.085 | 0.003 | 0.16
5818783 | 지상 9층 | 지상 9층 | 5818681 | 600 | 0.16 | 0.006 | 0.3
5818784 | 지상 9층 | 지상 9층 | 5818681 | 1600 | 0.41 | 0.016 | 0.81
5818789 | 지상 9층 | 지상 9층 | 5818681 | 754 | 0.1985 | 0.00754 | 0.387
5818790 | 지상 9층 | 지상 9층 | 5818681 | 754 | 0.1985 | 0.00754 | 0.387
5818791 | 지상 9층 | 지상 9층 | 5818681 | 729 | 0.19225 | 0.00729 | 0.3845
5818792 | 지상 9층 | 지상 9층 | 5818681 | 729 | 0.19225 | 0.00729 | 0.3845
5818793 | 지상 9층 | 지상 9층 | 5818681 | 300 | 0.085 | 0.003 | 0.16
5818794 | 지상 9층 | 지상 9층 | 5818681 | 600 | 0.16 | 0.006 | 0.3
5818795 | 지상 9층 | 지상 9층 | 5818681 | 1600 | 0.41 | 0.016 | 0.81
5818800 | 지상 9층 | 지상 9층 | 5818681 | 754 | 0.1985 | 0.00754 | 0.387
5818801 | 지상 9층 | 지상 9층 | 5818681 | 1120 | 0.29 | 0.0112 | 0.58
5818802 | 지상 9층 | 지상 9층 | 5818681 | 1120 | 0.29 | 0.0112 | 0.58
5818803 | 지상 9층 | 지상 9층 | 5818681 | 1120 | 0.29 | 0.0112 | 0.58
5818804 | 지상 9층 | 지상 9층 | 5818681 | 300 | 0.085 | 0.003 | 0.16
5818805 | 지상 9층 | 지상 9층 | 5818681 | 600 | 0.16 | 0.006 | 0.3
5818806 | 지상 9층 | 지상 9층 | 5818681 | 1600 | 0.41 | 0.016 | 0.81
5818811 | 지상 9층 | 지상 9층 | 5818681 | 1120 | 0.29 | 0.0112 | 0.58
5818812 | 지상 9층 | 지상 9층 | 5818681 | 741.5 | 0.195375 | 0.007415 | 0.38075
5818813 | 지상 9층 | 지상 9층 | 5818681 | 716.5 | 0.189125 | 0.007165 | 0.37825
5818814 | 지상 9층 | 지상 9층 | 5818681 | 716.5 | 0.189125 | 0.007165 | 0.37825
5818815 | 지상 9층 | 지상 9층 | 5818681 | 300 | 0.085 | 0.003 | 0.16
5818816 | 지상 9층 | 지상 9층 | 5818681 | 600 | 0.16 | 0.006 | 0.3
5818817 | 지상 9층 | 지상 9층 | 5818681 | 1600 | 0.41 | 0.016 | 0.81
5818822 | 지상 9층 | 지상 9층 | 5818681 | 741.5 | 0.195375 | 0.007415 | 0.38075
5818823 | 지상 9층 | 지상 9층 | 5818681 | 741.5 | 0.195375 | 0.007415 | 0.38075
5818824 | 지상 9층 | 지상 9층 | 5818681 | 716.5 | 0.189125 | 0.007165 | 0.37825
5818825 | 지상 9층 | 지상 9층 | 5818681 | 716.5 | 0.189125 | 0.007165 | 0.37825
5818826 | 지상 9층 | 지상 9층 | 5818681 | 300 | 0.085 | 0.003 | 0.16
5818827 | 지상 9층 | 지상 9층 | 5818681 | 600 | 0.16 | 0.006 | 0.3
5818828 | 지상 9층 | 지상 9층 | 5818681 | 1600 | 0.41 | 0.016 | 0.81
5818833 | 지상 9층 | 지상 9층 | 5818681 | 741.5 | 0.195375 | 0.007415 | 0.38075
5818834 | 지상 9층 | 지상 9층 | 5818681 | 741.5 | 0.195375 | 0.007415 | 0.38075
5818835 | 지상 9층 | 지상 9층 | 5818681 | 716.5 | 0.189125 | 0.007165 | 0.37825
5818836 | 지상 9층 | 지상 9층 | 5818681 | 716.5 | 0.189125 | 0.007165 | 0.37825
5818837 | 지상 9층 | 지상 9층 | 5818681 | 300 | 0.085 | 0.003 | 0.16
5818838 | 지상 9층 | 지상 9층 | 5818681 | 600 | 0.16 | 0.006 | 0.3
5818839 | 지상 9층 | 지상 9층 | 5818681 | 1600 | 0.41 | 0.016 | 0.81
5818844 | 지상 9층 | 지상 9층 | 5818681 | 741.5 | 0.195375 | 0.007415 | 0.38075
5818845 | 지상 9층 | 지상 9층 | 5818681 | 741.5 | 0.195375 | 0.007415 | 0.38075
5818846 | 지상 9층 | 지상 9층 | 5818681 | 716.5 | 0.189125 | 0.007165 | 0.37825
5818847 | 지상 9층 | 지상 9층 | 5818681 | 716.5 | 0.189125 | 0.007165 | 0.37825
5818848 | 지상 9층 | 지상 9층 | 5818681 | 300 | 0.085 | 0.003 | 0.16
5818849 | 지상 9층 | 지상 9층 | 5818681 | 600 | 0.16 | 0.006 | 0.3
5818850 | 지상 9층 | 지상 9층 | 5818681 | 1600 | 0.41 | 0.016 | 0.81
5818855 | 지상 9층 | 지상 9층 | 5818681 | 741.5 | 0.195375 | 0.007415 | 0.38075
5818856 | 지상 9층 | 지상 9층 | 5818681 | 1120 | 0.29 | 0.0112 | 0.58
5818857 | 지상 9층 | 지상 9층 | 5818681 | 1120 | 0.29 | 0.0112 | 0.58
5818858 | 지상 9층 | 지상 9층 | 5818681 | 1120 | 0.29 | 0.0112 | 0.58
5818859 | 지상 9층 | 지상 9층 | 5818681 | 300 | 0.085 | 0.003 | 0.16
5818860 | 지상 9층 | 지상 9층 | 5818681 | 600 | 0.16 | 0.006 | 0.3
5818861 | 지상 9층 | 지상 9층 | 5818681 | 1600 | 0.41 | 0.016 | 0.81
5818866 | 지상 9층 | 지상 9층 | 5818681 | 1120 | 0.29 | 0.0112 | 0.58
5818867 | 지상 9층 | 지상 9층 | 5818681 | 743.357 | 0.195839 | 0.00743357 | 0.381679
5818868 | 지상 9층 | 지상 9층 | 5818681 | 718.357 | 0.189589 | 0.00718357 | 0.379179
5818869 | 지상 9층 | 지상 9층 | 5818681 | 718.357 | 0.189589 | 0.00718357 | 0.379179
5818870 | 지상 9층 | 지상 9층 | 5818681 | 300 | 0.085 | 0.003 | 0.16
5818871 | 지상 9층 | 지상 9층 | 5818681 | 600 | 0.16 | 0.006 | 0.3
5818872 | 지상 9층 | 지상 9층 | 5818681 | 1600 | 0.41 | 0.016 | 0.81
5818877 | 지상 9층 | 지상 9층 | 5818681 | 743.357 | 0.195839 | 0.00743357 | 0.381679
5818878 | 지상 9층 | 지상 9층 | 5818681 | 743.357 | 0.195839 | 0.00743357 | 0.381679
5818879 | 지상 9층 | 지상 9층 | 5818681 | 718.357 | 0.189589 | 0.00718357 | 0.379179
5818880 | 지상 9층 | 지상 9층 | 5818681 | 718.357 | 0.189589 | 0.00718357 | 0.379179
5818881 | 지상 9층 | 지상 9층 | 5818681 | 300 | 0.085 | 0.003 | 0.16
5818882 | 지상 9층 | 지상 9층 | 5818681 | 600 | 0.16 | 0.006 | 0.3
5818883 | 지상 9층 | 지상 9층 | 5818681 | 1600 | 0.41 | 0.016 | 0.81
5818888 | 지상 9층 | 지상 9층 | 5818681 | 743.357 | 0.195839 | 0.00743357 | 0.381679
5818889 | 지상 9층 | 지상 9층 | 5818681 | 743.357 | 0.195839 | 0.00743357 | 0.381679
5818890 | 지상 9층 | 지상 9층 | 5818681 | 718.357 | 0.189589 | 0.00718357 | 0.379179
5818891 | 지상 9층 | 지상 9층 | 5818681 | 718.357 | 0.189589 | 0.00718357 | 0.379179
5818892 | 지상 9층 | 지상 9층 | 5818681 | 300 | 0.085 | 0.003 | 0.16
5818893 | 지상 9층 | 지상 9층 | 5818681 | 600 | 0.16 | 0.006 | 0.3
5818894 | 지상 9층 | 지상 9층 | 5818681 | 1600 | 0.41 | 0.016 | 0.81
5818899 | 지상 9층 | 지상 9층 | 5818681 | 743.357 | 0.195839 | 0.00743357 | 0.381679
5818900 | 지상 9층 | 지상 9층 | 5818681 | 743.357 | 0.195839 | 0.00743357 | 0.381679
5818901 | 지상 9층 | 지상 9층 | 5818681 | 718.357 | 0.189589 | 0.00718357 | 0.379179
5818902 | 지상 9층 | 지상 9층 | 5818681 | 718.357 | 0.189589 | 0.00718357 | 0.379179
5818903 | 지상 9층 | 지상 9층 | 5818681 | 300 | 0.085 | 0.003 | 0.16
5818904 | 지상 9층 | 지상 9층 | 5818681 | 600 | 0.16 | 0.006 | 0.3
5818905 | 지상 9층 | 지상 9층 | 5818681 | 1600 | 0.41 | 0.016 | 0.81
5818910 | 지상 9층 | 지상 9층 | 5818681 | 743.357 | 0.195839 | 0.00743357 | 0.381679
5818911 | 지상 9층 | 지상 9층 | 5818681 | 743.357 | 0.195839 | 0.00743357 | 0.381679
5818912 | 지상 9층 | 지상 9층 | 5818681 | 718.357 | 0.189589 | 0.00718357 | 0.379179
5818913 | 지상 9층 | 지상 9층 | 5818681 | 718.357 | 0.189589 | 0.00718357 | 0.379179
5818914 | 지상 9층 | 지상 9층 | 5818681 | 300 | 0.085 | 0.003 | 0.16
5818915 | 지상 9층 | 지상 9층 | 5818681 | 600 | 0.16 | 0.006 | 0.3
5818916 | 지상 9층 | 지상 9층 | 5818681 | 1600 | 0.41 | 0.016 | 0.81
5818921 | 지상 9층 | 지상 9층 | 5818681 | 743.357 | 0.195839 | 0.00743357 | 0.381679
5818922 | 지상 9층 | 지상 9층 | 5818681 | 743.357 | 0.195839 | 0.00743357 | 0.381679
5818923 | 지상 9층 | 지상 9층 | 5818681 | 718.357 | 0.189589 | 0.00718357 | 0.379179
5818924 | 지상 9층 | 지상 9층 | 5818681 | 718.357 | 0.189589 | 0.00718357 | 0.379179
5818925 | 지상 9층 | 지상 9층 | 5818681 | 300 | 0.085 | 0.003 | 0.16
5818926 | 지상 9층 | 지상 9층 | 5818681 | 600 | 0.16 | 0.006 | 0.3
5818927 | 지상 9층 | 지상 9층 | 5818681 | 1600 | 0.41 | 0.016 | 0.81
5818932 | 지상 9층 | 지상 9층 | 5818681 | 743.357 | 0.195839 | 0.00743357 | 0.381679
5818933 | 지상 9층 | 지상 9층 | 5818681 | 743.357 | 0.195839 | 0.00743357 | 0.381679
5818934 | 지상 9층 | 지상 9층 | 5818681 | 718.357 | 0.189589 | 0.00718357 | 0.379179
5818935 | 지상 9층 | 지상 9층 | 5818681 | 718.357 | 0.189589 | 0.00718357 | 0.379179
5818936 | 지상 9층 | 지상 9층 | 5818681 | 300 | 0.085 | 0.003 | 0.16
5818937 | 지상 9층 | 지상 9층 | 5818681 | 600 | 0.16 | 0.006 | 0.3
5818938 | 지상 9층 | 지상 9층 | 5818681 | 1600 | 0.41 | 0.016 | 0.81
5818943 | 지상 9층 | 지상 9층 | 5818681 | 743.357 | 0.195839 | 0.00743357 | 0.381679
5818944 | 지상 9층 | 지상 9층 | 5818681 | 912.5 | 0.238125 | 0.009125 | 0.47625
5818945 | 지상 9층 | 지상 9층 | 5818681 | 912.5 | 0.238125 | 0.009125 | 0.47625
5818946 | 지상 9층 | 지상 9층 | 5818681 | 912.5 | 0.238125 | 0.009125 | 0.47625
5818947 | 지상 9층 | 지상 9층 | 5818681 | 300 | 0.085 | 0.003 | 0.16
5818948 | 지상 9층 | 지상 9층 | 5818681 | 600 | 0.16 | 0.006 | 0.3
5818949 | 지상 9층 | 지상 9층 | 5818681 | 1600 | 0.41 | 0.016 | 0.81
5818954 | 지상 9층 | 지상 9층 | 5818681 | 828.5 | 0.217125 | 0.008285 | 0.42425
5818955 | 지상 9층 | 지상 9층 | 5818681 | 828.5 | 0.217125 | 0.008285 | 0.42425
5818956 | 지상 9층 | 지상 9층 | 5818681 | 803.5 | 0.210875 | 0.008035 | 0.42175
5818957 | 지상 9층 | 지상 9층 | 5818681 | 803.5 | 0.210875 | 0.008035 | 0.42175
5818958 | 지상 9층 | 지상 9층 | 5818681 | 650 | 0.1725 | 0.0065 | 0.345
5818963 | 지상 9층 | 지상 9층 | 5818681 | 828.5 | 0.217125 | 0.008285 | 0.42425
5818964 | 지상 9층 | 지상 9층 | 5818681 | 828.5 | 0.217125 | 0.008285 | 0.42425
5818965 | 지상 9층 | 지상 9층 | 5818681 | 803.5 | 0.210875 | 0.008035 | 0.42175
5818966 | 지상 9층 | 지상 9층 | 5818681 | 803.5 | 0.210875 | 0.008035 | 0.42175
5818967 | 지상 9층 | 지상 9층 | 5818681 | 650 | 0.1725 | 0.0065 | 0.345
5818972 | 지상 9층 | 지상 9층 | 5818681 | 828.5 | 0.217125 | 0.008285 | 0.42425
5818973 | 지상 9층 | 지상 9층 | 5818681 | 828.5 | 0.217125 | 0.008285 | 0.42425
5818974 | 지상 9층 | 지상 9층 | 5818681 | 803.5 | 0.210875 | 0.008035 | 0.42175
5818975 | 지상 9층 | 지상 9층 | 5818681 | 803.5 | 0.210875 | 0.008035 | 0.42175
5818976 | 지상 9층 | 지상 9층 | 5818681 | 650 | 0.1725 | 0.0065 | 0.345
5818981 | 지상 9층 | 지상 9층 | 5818681 | 828.5 | 0.217125 | 0.008285 | 0.42425
5818982 | 지상 9층 | 지상 9층 | 5818681 | 828.5 | 0.217125 | 0.008285 | 0.42425
5818983 | 지상 9층 | 지상 9층 | 5818681 | 803.5 | 0.210875 | 0.008035 | 0.42175
5818984 | 지상 9층 | 지상 9층 | 5818681 | 803.5 | 0.210875 | 0.008035 | 0.42175
5818985 | 지상 9층 | 지상 9층 | 5818681 | 650 | 0.1725 | 0.0065 | 0.345
5818990 | 지상 9층 | 지상 9층 | 5818681 | 754 | 0.1985 | 0.00754 | 0.387
5818991 | 지상 9층 | 지상 9층 | 5818681 | 754 | 0.1985 | 0.00754 | 0.387
5818992 | 지상 9층 | 지상 9층 | 5818681 | 729 | 0.19225 | 0.00729 | 0.3845
5818993 | 지상 9층 | 지상 9층 | 5818681 | 729 | 0.19225 | 0.00729 | 0.3845
5818994 | 지상 9층 | 지상 9층 | 5818681 | 650 | 0.1725 | 0.0065 | 0.345
5818999 | 지상 9층 | 지상 9층 | 5818681 | 754 | 0.1985 | 0.00754 | 0.387
5819000 | 지상 9층 | 지상 9층 | 5818681 | 754 | 0.1985 | 0.00754 | 0.387
5819001 | 지상 9층 | 지상 9층 | 5818681 | 729 | 0.19225 | 0.00729 | 0.3845
5819002 | 지상 9층 | 지상 9층 | 5818681 | 729 | 0.19225 | 0.00729 | 0.3845
5819003 | 지상 9층 | 지상 9층 | 5818681 | 650 | 0.1725 | 0.0065 | 0.345
5819008 | 지상 9층 | 지상 9층 | 5818681 | 754 | 0.1985 | 0.00754 | 0.387
5819009 | 지상 9층 | 지상 9층 | 5818681 | 754 | 0.1985 | 0.00754 | 0.387
5819010 | 지상 9층 | 지상 9층 | 5818681 | 729 | 0.19225 | 0.00729 | 0.3845
5819011 | 지상 9층 | 지상 9층 | 5818681 | 729 | 0.19225 | 0.00729 | 0.3845
5819012 | 지상 9층 | 지상 9층 | 5818681 | 650 | 0.1725 | 0.0065 | 0.345
5819017 | 지상 9층 | 지상 9층 | 5818681 | 754 | 0.1985 | 0.00754 | 0.387
5819018 | 지상 9층 | 지상 9층 | 5818681 | 754 | 0.1985 | 0.00754 | 0.387
5819019 | 지상 9층 | 지상 9층 | 5818681 | 729 | 0.19225 | 0.00729 | 0.3845
5819020 | 지상 9층 | 지상 9층 | 5818681 | 729 | 0.19225 | 0.00729 | 0.3845
5819021 | 지상 9층 | 지상 9층 | 5818681 | 650 | 0.1725 | 0.0065 | 0.345
5819026 | 지상 9층 | 지상 9층 | 5818681 | 741.5 | 0.195375 | 0.007415 | 0.38075
5819027 | 지상 9층 | 지상 9층 | 5818681 | 741.5 | 0.195375 | 0.007415 | 0.38075
5819028 | 지상 9층 | 지상 9층 | 5818681 | 716.5 | 0.189125 | 0.007165 | 0.37825
5819029 | 지상 9층 | 지상 9층 | 5818681 | 716.5 | 0.189125 | 0.007165 | 0.37825
5819030 | 지상 9층 | 지상 9층 | 5818681 | 650 | 0.1725 | 0.0065 | 0.345
5819035 | 지상 9층 | 지상 9층 | 5818681 | 741.5 | 0.195375 | 0.007415 | 0.38075
5819036 | 지상 9층 | 지상 9층 | 5818681 | 741.5 | 0.195375 | 0.007415 | 0.38075
5819037 | 지상 9층 | 지상 9층 | 5818681 | 716.5 | 0.189125 | 0.007165 | 0.37825
5819038 | 지상 9층 | 지상 9층 | 5818681 | 716.5 | 0.189125 | 0.007165 | 0.37825
5819039 | 지상 9층 | 지상 9층 | 5818681 | 650 | 0.1725 | 0.0065 | 0.345
5819044 | 지상 9층 | 지상 9층 | 5818681 | 741.5 | 0.195375 | 0.007415 | 0.38075
5819045 | 지상 9층 | 지상 9층 | 5818681 | 741.5 | 0.195375 | 0.007415 | 0.38075
5819046 | 지상 9층 | 지상 9층 | 5818681 | 716.5 | 0.189125 | 0.007165 | 0.37825
5819047 | 지상 9층 | 지상 9층 | 5818681 | 716.5 | 0.189125 | 0.007165 | 0.37825
5819048 | 지상 9층 | 지상 9층 | 5818681 | 650 | 0.1725 | 0.0065 | 0.345
5819053 | 지상 9층 | 지상 9층 | 5818681 | 741.5 | 0.195375 | 0.007415 | 0.38075
5819054 | 지상 9층 | 지상 9층 | 5818681 | 741.5 | 0.195375 | 0.007415 | 0.38075
5819055 | 지상 9층 | 지상 9층 | 5818681 | 716.5 | 0.189125 | 0.007165 | 0.37825
5819056 | 지상 9층 | 지상 9층 | 5818681 | 716.5 | 0.189125 | 0.007165 | 0.37825
5819057 | 지상 9층 | 지상 9층 | 5818681 | 650 | 0.1725 | 0.0065 | 0.345
5819062 | 지상 9층 | 지상 9층 | 5818681 | 743.357 | 0.195839 | 0.00743357 | 0.381679
5819063 | 지상 9층 | 지상 9층 | 5818681 | 743.357 | 0.195839 | 0.00743357 | 0.381679
5819064 | 지상 9층 | 지상 9층 | 5818681 | 718.357 | 0.189589 | 0.00718357 | 0.379179
5819065 | 지상 9층 | 지상 9층 | 5818681 | 718.357 | 0.189589 | 0.00718357 | 0.379179
5819066 | 지상 9층 | 지상 9층 | 5818681 | 650 | 0.1725 | 0.0065 | 0.345
5819071 | 지상 9층 | 지상 9층 | 5818681 | 743.357 | 0.195839 | 0.00743357 | 0.381679
5819072 | 지상 9층 | 지상 9층 | 5818681 | 743.357 | 0.195839 | 0.00743357 | 0.381679
5819073 | 지상 9층 | 지상 9층 | 5818681 | 718.357 | 0.189589 | 0.00718357 | 0.379179
5819074 | 지상 9층 | 지상 9층 | 5818681 | 718.357 | 0.189589 | 0.00718357 | 0.379179
5819075 | 지상 9층 | 지상 9층 | 5818681 | 650 | 0.1725 | 0.0065 | 0.345
5819080 | 지상 9층 | 지상 9층 | 5818681 | 743.357 | 0.195839 | 0.00743357 | 0.381679
5819081 | 지상 9층 | 지상 9층 | 5818681 | 743.357 | 0.195839 | 0.00743357 | 0.381679
5819082 | 지상 9층 | 지상 9층 | 5818681 | 718.357 | 0.189589 | 0.00718357 | 0.379179
5819083 | 지상 9층 | 지상 9층 | 5818681 | 718.357 | 0.189589 | 0.00718357 | 0.379179
5819084 | 지상 9층 | 지상 9층 | 5818681 | 650 | 0.1725 | 0.0065 | 0.345
5819089 | 지상 9층 | 지상 9층 | 5818681 | 743.357 | 0.195839 | 0.00743357 | 0.381679
5819090 | 지상 9층 | 지상 9층 | 5818681 | 743.357 | 0.195839 | 0.00743357 | 0.381679
5819091 | 지상 9층 | 지상 9층 | 5818681 | 718.357 | 0.189589 | 0.00718357 | 0.379179
5819092 | 지상 9층 | 지상 9층 | 5818681 | 718.357 | 0.189589 | 0.00718357 | 0.379179
5819093 | 지상 9층 | 지상 9층 | 5818681 | 650 | 0.1725 | 0.0065 | 0.345
5819098 | 지상 9층 | 지상 9층 | 5818681 | 743.357 | 0.195839 | 0.00743357 | 0.381679
5819099 | 지상 9층 | 지상 9층 | 5818681 | 743.357 | 0.195839 | 0.00743357 | 0.381679
5819100 | 지상 9층 | 지상 9층 | 5818681 | 718.357 | 0.189589 | 0.00718357 | 0.379179
5819101 | 지상 9층 | 지상 9층 | 5818681 | 718.357 | 0.189589 | 0.00718357 | 0.379179
5819102 | 지상 9층 | 지상 9층 | 5818681 | 650 | 0.1725 | 0.0065 | 0.345
5819107 | 지상 9층 | 지상 9층 | 5818681 | 743.357 | 0.195839 | 0.00743357 | 0.381679
5819108 | 지상 9층 | 지상 9층 | 5818681 | 743.357 | 0.195839 | 0.00743357 | 0.381679
5819109 | 지상 9층 | 지상 9층 | 5818681 | 718.357 | 0.189589 | 0.00718357 | 0.379179
5819110 | 지상 9층 | 지상 9층 | 5818681 | 718.357 | 0.189589 | 0.00718357 | 0.379179
5819111 | 지상 9층 | 지상 9층 | 5818681 | 650 | 0.1725 | 0.0065 | 0.345
5819116 | 지상 9층 | 지상 9층 | 5818681 | 743.357 | 0.195839 | 0.00743357 | 0.381679
5819117 | 지상 9층 | 지상 9층 | 5818681 | 743.357 | 0.195839 | 0.00743357 | 0.381679
5819118 | 지상 9층 | 지상 9층 | 5818681 | 718.357 | 0.189589 | 0.00718357 | 0.379179
5819119 | 지상 9층 | 지상 9층 | 5818681 | 718.357 | 0.189589 | 0.00718357 | 0.379179
5819120 | 지상 9층 | 지상 9층 | 5818681 | 650 | 0.1725 | 0.0065 | 0.345
5819256 | 지상 8층 | 지상 8층 | 5819254 | 892.928 | 0.233232 | 0.00892928 | 0.466464
5819257 | 지상 8층 | 지상 8층 | 5819254 | 912.816 | 0.238204 | 0.00912816 | 0.476408
5819262 | 지상 8층 | 지상 8층 | 5819254 | 912.816 | 0.238204 | 0.00912816 | 0.476408
5819266 | 지상 8층 | 지상 8층 | 5819254 | 912.816 | 0.238204 | 0.00912816 | 0.476408
5819271 | 지상 8층 | 지상 8층 | 5819254 | 912.816 | 0.238204 | 0.00912816 | 0.476408
5819272 | 지상 8층 | 지상 8층 | 5819254 | 970 | 0.2525 | 0.0097 | 0.495
5819273 | 지상 8층 | 지상 8층 | 5819254 | 945 | 0.24625 | 0.00945 | 0.4925
5819274 | 지상 8층 | 지상 8층 | 5819254 | 945 | 0.24625 | 0.00945 | 0.4925
5819275 | 지상 8층 | 지상 8층 | 5819254 | 300 | 0.085 | 0.003 | 0.16
5819276 | 지상 8층 | 지상 8층 | 5819254 | 600 | 0.16 | 0.006 | 0.3
5819277 | 지상 8층 | 지상 8층 | 5819254 | 1100 | 0.285 | 0.011 | 0.56
5819282 | 지상 8층 | 지상 8층 | 5819254 | 940 | 0.245 | 0.0094 | 0.48
5819283 | 지상 8층 | 지상 8층 | 5819254 | 940 | 0.245 | 0.0094 | 0.48
5819284 | 지상 8층 | 지상 8층 | 5819254 | 915 | 0.23875 | 0.00915 | 0.4775
5819285 | 지상 8층 | 지상 8층 | 5819254 | 915 | 0.23875 | 0.00915 | 0.4775
5819286 | 지상 8층 | 지상 8층 | 5819254 | 300 | 0.085 | 0.003 | 0.16
5819287 | 지상 8층 | 지상 8층 | 5819254 | 600 | 0.16 | 0.006 | 0.3
5819288 | 지상 8층 | 지상 8층 | 5819254 | 1100 | 0.285 | 0.011 | 0.56
5819293 | 지상 8층 | 지상 8층 | 5819254 | 940 | 0.245 | 0.0094 | 0.48
5819294 | 지상 8층 | 지상 8층 | 5819254 | 940 | 0.245 | 0.0094 | 0.48
5819295 | 지상 8층 | 지상 8층 | 5819254 | 915 | 0.23875 | 0.00915 | 0.4775
5819296 | 지상 8층 | 지상 8층 | 5819254 | 915 | 0.23875 | 0.00915 | 0.4775
5819297 | 지상 8층 | 지상 8층 | 5819254 | 300 | 0.085 | 0.003 | 0.16
5819298 | 지상 8층 | 지상 8층 | 5819254 | 600 | 0.16 | 0.006 | 0.3
5819299 | 지상 8층 | 지상 8층 | 5819254 | 1100 | 0.285 | 0.011 | 0.56
5819304 | 지상 8층 | 지상 8층 | 5819254 | 940 | 0.245 | 0.0094 | 0.48
5819305 | 지상 8층 | 지상 8층 | 5819254 | 940 | 0.245 | 0.0094 | 0.48
5819306 | 지상 8층 | 지상 8층 | 5819254 | 915 | 0.23875 | 0.00915 | 0.4775
5819307 | 지상 8층 | 지상 8층 | 5819254 | 915 | 0.23875 | 0.00915 | 0.4775
5819308 | 지상 8층 | 지상 8층 | 5819254 | 300 | 0.085 | 0.003 | 0.16
5819309 | 지상 8층 | 지상 8층 | 5819254 | 600 | 0.16 | 0.006 | 0.3
5819310 | 지상 8층 | 지상 8층 | 5819254 | 1100 | 0.285 | 0.011 | 0.56
5819315 | 지상 8층 | 지상 8층 | 5819254 | 940 | 0.245 | 0.0094 | 0.48
5819316 | 지상 8층 | 지상 8층 | 5819254 | 940 | 0.245 | 0.0094 | 0.48
5819317 | 지상 8층 | 지상 8층 | 5819254 | 915 | 0.23875 | 0.00915 | 0.4775
5819318 | 지상 8층 | 지상 8층 | 5819254 | 915 | 0.23875 | 0.00915 | 0.4775
5819319 | 지상 8층 | 지상 8층 | 5819254 | 300 | 0.085 | 0.003 | 0.16
5819320 | 지상 8층 | 지상 8층 | 5819254 | 600 | 0.16 | 0.006 | 0.3
5819321 | 지상 8층 | 지상 8층 | 5819254 | 1100 | 0.285 | 0.011 | 0.56
5819326 | 지상 8층 | 지상 8층 | 5819254 | 940 | 0.245 | 0.0094 | 0.48
5819327 | 지상 8층 | 지상 8층 | 5819254 | 940 | 0.245 | 0.0094 | 0.48
5819328 | 지상 8층 | 지상 8층 | 5819254 | 915 | 0.23875 | 0.00915 | 0.4775
5819329 | 지상 8층 | 지상 8층 | 5819254 | 915 | 0.23875 | 0.00915 | 0.4775
5819330 | 지상 8층 | 지상 8층 | 5819254 | 300 | 0.085 | 0.003 | 0.16
5819331 | 지상 8층 | 지상 8층 | 5819254 | 600 | 0.16 | 0.006 | 0.3
5819332 | 지상 8층 | 지상 8층 | 5819254 | 1100 | 0.285 | 0.011 | 0.56
5819337 | 지상 8층 | 지상 8층 | 5819254 | 970 | 0.2525 | 0.0097 | 0.495
5819338 | 지상 8층 | 지상 8층 | 5819254 | 1010 | 0.2625 | 0.0101 | 0.525
5819339 | 지상 8층 | 지상 8층 | 5819254 | 1010 | 0.2625 | 0.0101 | 0.525
5819340 | 지상 8층 | 지상 8층 | 5819254 | 1010 | 0.2625 | 0.0101 | 0.525
5819341 | 지상 8층 | 지상 8층 | 5819254 | 300 | 0.085 | 0.003 | 0.16
5819342 | 지상 8층 | 지상 8층 | 5819254 | 600 | 0.16 | 0.006 | 0.3
5819343 | 지상 8층 | 지상 8층 | 5819254 | 1100 | 0.285 | 0.011 | 0.56
5819348 | 지상 8층 | 지상 8층 | 5819254 | 1010 | 0.2625 | 0.0101 | 0.525
5819349 | 지상 8층 | 지상 8층 | 5819254 | 1080 | 0.28 | 0.0108 | 0.55
5819350 | 지상 8층 | 지상 8층 | 5819254 | 1055 | 0.27375 | 0.01055 | 0.5475
5819351 | 지상 8층 | 지상 8층 | 5819254 | 1055 | 0.27375 | 0.01055 | 0.5475
5819352 | 지상 8층 | 지상 8층 | 5819254 | 300 | 0.085 | 0.003 | 0.16
5819353 | 지상 8층 | 지상 8층 | 5819254 | 600 | 0.16 | 0.006 | 0.3
5819354 | 지상 8층 | 지상 8층 | 5819254 | 1100 | 0.285 | 0.011 | 0.56
5819359 | 지상 8층 | 지상 8층 | 5819254 | 1110 | 0.2875 | 0.0111 | 0.565
5819360 | 지상 8층 | 지상 8층 | 5819254 | 1010 | 0.2625 | 0.0101 | 0.525
5819361 | 지상 8층 | 지상 8층 | 5819254 | 1010 | 0.2625 | 0.0101 | 0.525
5819362 | 지상 8층 | 지상 8층 | 5819254 | 1010 | 0.2625 | 0.0101 | 0.525
5819363 | 지상 8층 | 지상 8층 | 5819254 | 300 | 0.085 | 0.003 | 0.16
5819364 | 지상 8층 | 지상 8층 | 5819254 | 600 | 0.16 | 0.006 | 0.3
5819365 | 지상 8층 | 지상 8층 | 5819254 | 1100 | 0.285 | 0.011 | 0.56
5819370 | 지상 8층 | 지상 8층 | 5819254 | 1010 | 0.2625 | 0.0101 | 0.525
5819371 | 지상 8층 | 지상 8층 | 5819254 | 940 | 0.245 | 0.0094 | 0.48
5819372 | 지상 8층 | 지상 8층 | 5819254 | 915 | 0.23875 | 0.00915 | 0.4775
5819373 | 지상 8층 | 지상 8층 | 5819254 | 915 | 0.23875 | 0.00915 | 0.4775
5819374 | 지상 8층 | 지상 8층 | 5819254 | 300 | 0.085 | 0.003 | 0.16
5819375 | 지상 8층 | 지상 8층 | 5819254 | 600 | 0.16 | 0.006 | 0.3
5819376 | 지상 8층 | 지상 8층 | 5819254 | 1100 | 0.285 | 0.011 | 0.56
5819381 | 지상 8층 | 지상 8층 | 5819254 | 940 | 0.245 | 0.0094 | 0.48
5819382 | 지상 8층 | 지상 8층 | 5819254 | 940 | 0.245 | 0.0094 | 0.48
5819383 | 지상 8층 | 지상 8층 | 5819254 | 915 | 0.23875 | 0.00915 | 0.4775
5819384 | 지상 8층 | 지상 8층 | 5819254 | 915 | 0.23875 | 0.00915 | 0.4775
5819385 | 지상 8층 | 지상 8층 | 5819254 | 300 | 0.085 | 0.003 | 0.16
5819386 | 지상 8층 | 지상 8층 | 5819254 | 600 | 0.16 | 0.006 | 0.3
5819387 | 지상 8층 | 지상 8층 | 5819254 | 1100 | 0.285 | 0.011 | 0.56
5819392 | 지상 8층 | 지상 8층 | 5819254 | 940 | 0.245 | 0.0094 | 0.48
5819393 | 지상 8층 | 지상 8층 | 5819254 | 940 | 0.245 | 0.0094 | 0.48
5819394 | 지상 8층 | 지상 8층 | 5819254 | 915 | 0.23875 | 0.00915 | 0.4775
5819395 | 지상 8층 | 지상 8층 | 5819254 | 915 | 0.23875 | 0.00915 | 0.4775
5819396 | 지상 8층 | 지상 8층 | 5819254 | 300 | 0.085 | 0.003 | 0.16
5819397 | 지상 8층 | 지상 8층 | 5819254 | 600 | 0.16 | 0.006 | 0.3
5819398 | 지상 8층 | 지상 8층 | 5819254 | 1100 | 0.285 | 0.011 | 0.56
5819403 | 지상 8층 | 지상 8층 | 5819254 | 940 | 0.245 | 0.0094 | 0.48
5819404 | 지상 8층 | 지상 8층 | 5819254 | 940 | 0.245 | 0.0094 | 0.48
5819405 | 지상 8층 | 지상 8층 | 5819254 | 915 | 0.23875 | 0.00915 | 0.4775
5819406 | 지상 8층 | 지상 8층 | 5819254 | 915 | 0.23875 | 0.00915 | 0.4775
5819407 | 지상 8층 | 지상 8층 | 5819254 | 300 | 0.085 | 0.003 | 0.16
5819408 | 지상 8층 | 지상 8층 | 5819254 | 600 | 0.16 | 0.006 | 0.3
5819409 | 지상 8층 | 지상 8층 | 5819254 | 1100 | 0.285 | 0.011 | 0.56
5819414 | 지상 8층 | 지상 8층 | 5819254 | 940 | 0.245 | 0.0094 | 0.48
5819415 | 지상 8층 | 지상 8층 | 5819254 | 940 | 0.245 | 0.0094 | 0.48
5819416 | 지상 8층 | 지상 8층 | 5819254 | 915 | 0.23875 | 0.00915 | 0.4775
5819417 | 지상 8층 | 지상 8층 | 5819254 | 915 | 0.23875 | 0.00915 | 0.4775
5819418 | 지상 8층 | 지상 8층 | 5819254 | 300 | 0.085 | 0.003 | 0.16
5819419 | 지상 8층 | 지상 8층 | 5819254 | 600 | 0.16 | 0.006 | 0.3
5819420 | 지상 8층 | 지상 8층 | 5819254 | 1100 | 0.285 | 0.011 | 0.56
5819425 | 지상 8층 | 지상 8층 | 5819254 | 935 | 0.24375 | 0.00935 | 0.4775
5819426 | 지상 8층 | 지상 8층 | 5819254 | 1010 | 0.2625 | 0.0101 | 0.525
5819427 | 지상 8층 | 지상 8층 | 5819254 | 1010 | 0.2625 | 0.0101 | 0.525
5819428 | 지상 8층 | 지상 8층 | 5819254 | 1010 | 0.2625 | 0.0101 | 0.525
5819429 | 지상 8층 | 지상 8층 | 5819254 | 300 | 0.085 | 0.003 | 0.16
5819430 | 지상 8층 | 지상 8층 | 5819254 | 600 | 0.16 | 0.006 | 0.3
5819431 | 지상 8층 | 지상 8층 | 5819254 | 1100 | 0.285 | 0.011 | 0.56
5819436 | 지상 8층 | 지상 8층 | 5819254 | 1010 | 0.2625 | 0.0101 | 0.525
5819437 | 지상 8층 | 지상 8층 | 5819254 | 995 | 0.25875 | 0.00995 | 0.5075
5819438 | 지상 8층 | 지상 8층 | 5819254 | 970 | 0.2525 | 0.0097 | 0.505
5819439 | 지상 8층 | 지상 8층 | 5819254 | 970 | 0.2525 | 0.0097 | 0.505
5819440 | 지상 8층 | 지상 8층 | 5819254 | 300 | 0.085 | 0.003 | 0.16
5819441 | 지상 8층 | 지상 8층 | 5819254 | 600 | 0.16 | 0.006 | 0.3
5819442 | 지상 8층 | 지상 8층 | 5819254 | 1100 | 0.285 | 0.011 | 0.56
5819447 | 지상 8층 | 지상 8층 | 5819254 | 940 | 0.245 | 0.0094 | 0.48
5819448 | 지상 8층 | 지상 8층 | 5819254 | 940 | 0.245 | 0.0094 | 0.48
5819449 | 지상 8층 | 지상 8층 | 5819254 | 915 | 0.23875 | 0.00915 | 0.4775
5819450 | 지상 8층 | 지상 8층 | 5819254 | 915 | 0.23875 | 0.00915 | 0.4775
5819451 | 지상 8층 | 지상 8층 | 5819254 | 300 | 0.085 | 0.003 | 0.16
5819452 | 지상 8층 | 지상 8층 | 5819254 | 600 | 0.16 | 0.006 | 0.3
5819453 | 지상 8층 | 지상 8층 | 5819254 | 1100 | 0.285 | 0.011 | 0.56
5819458 | 지상 8층 | 지상 8층 | 5819254 | 940 | 0.245 | 0.0094 | 0.48
5819459 | 지상 8층 | 지상 8층 | 5819254 | 940 | 0.245 | 0.0094 | 0.48
5819460 | 지상 8층 | 지상 8층 | 5819254 | 915 | 0.23875 | 0.00915 | 0.4775
5819461 | 지상 8층 | 지상 8층 | 5819254 | 915 | 0.23875 | 0.00915 | 0.4775
5819462 | 지상 8층 | 지상 8층 | 5819254 | 300 | 0.085 | 0.003 | 0.16
5819463 | 지상 8층 | 지상 8층 | 5819254 | 600 | 0.16 | 0.006 | 0.3
5819464 | 지상 8층 | 지상 8층 | 5819254 | 1100 | 0.285 | 0.011 | 0.56
5819469 | 지상 8층 | 지상 8층 | 5819254 | 940 | 0.245 | 0.0094 | 0.48
5819470 | 지상 8층 | 지상 8층 | 5819254 | 940 | 0.245 | 0.0094 | 0.48
5819471 | 지상 8층 | 지상 8층 | 5819254 | 915 | 0.23875 | 0.00915 | 0.4775
5819472 | 지상 8층 | 지상 8층 | 5819254 | 915 | 0.23875 | 0.00915 | 0.4775
5819473 | 지상 8층 | 지상 8층 | 5819254 | 300 | 0.085 | 0.003 | 0.16
5819474 | 지상 8층 | 지상 8층 | 5819254 | 600 | 0.16 | 0.006 | 0.3
5819475 | 지상 8층 | 지상 8층 | 5819254 | 1100 | 0.285 | 0.011 | 0.56
5819480 | 지상 8층 | 지상 8층 | 5819254 | 940 | 0.245 | 0.0094 | 0.48
5819481 | 지상 8층 | 지상 8층 | 5819254 | 1015 | 0.26375 | 0.01015 | 0.5275
5819482 | 지상 8층 | 지상 8층 | 5819254 | 1015 | 0.26375 | 0.01015 | 0.5275
5819483 | 지상 8층 | 지상 8층 | 5819254 | 1015 | 0.26375 | 0.01015 | 0.5275
5819484 | 지상 8층 | 지상 8층 | 5819254 | 300 | 0.085 | 0.003 | 0.16
5819485 | 지상 8층 | 지상 8층 | 5819254 | 600 | 0.16 | 0.006 | 0.3
5819486 | 지상 8층 | 지상 8층 | 5819254 | 1100 | 0.285 | 0.011 | 0.56
5819491 | 지상 8층 | 지상 8층 | 5819254 | 1015 | 0.26375 | 0.01015 | 0.5275
5819492 | 지상 8층 | 지상 8층 | 5819254 | 892.928 | 0.233232 | 0.00892928 | 0.466464
5819493 | 지상 8층 | 지상 8층 | 5819254 | 892.928 | 0.233232 | 0.00892928 | 0.466464
5819494 | 지상 8층 | 지상 8층 | 5819254 | 892.928 | 0.233232 | 0.00892928 | 0.466464
5819495 | 지상 8층 | 지상 8층 | 5819254 | 300 | 0.085 | 0.003 | 0.16
5819496 | 지상 8층 | 지상 8층 | 5819254 | 600 | 0.16 | 0.006 | 0.3
5819497 | 지상 8층 | 지상 8층 | 5819254 | 1100 | 0.285 | 0.011 | 0.56
5819502 | 지상 8층 | 지상 8층 | 5819254 | 970 | 0.2525 | 0.0097 | 0.495
5819503 | 지상 8층 | 지상 8층 | 5819254 | 940 | 0.245 | 0.0094 | 0.48
5819504 | 지상 8층 | 지상 8층 | 5819254 | 915 | 0.23875 | 0.00915 | 0.4775
5819505 | 지상 8층 | 지상 8층 | 5819254 | 915 | 0.23875 | 0.00915 | 0.4775
5819506 | 지상 8층 | 지상 8층 | 5819254 | 650 | 0.1725 | 0.0065 | 0.345
5819511 | 지상 8층 | 지상 8층 | 5819254 | 940 | 0.245 | 0.0094 | 0.48
5819512 | 지상 8층 | 지상 8층 | 5819254 | 915 | 0.23875 | 0.00915 | 0.4775
5819513 | 지상 8층 | 지상 8층 | 5819254 | 915 | 0.23875 | 0.00915 | 0.4775
5819514 | 지상 8층 | 지상 8층 | 5819254 | 940 | 0.245 | 0.0094 | 0.48
5819515 | 지상 8층 | 지상 8층 | 5819254 | 650 | 0.1725 | 0.0065 | 0.345
5819520 | 지상 8층 | 지상 8층 | 5819254 | 940 | 0.245 | 0.0094 | 0.48
5819521 | 지상 8층 | 지상 8층 | 5819254 | 915 | 0.23875 | 0.00915 | 0.4775
5819522 | 지상 8층 | 지상 8층 | 5819254 | 915 | 0.23875 | 0.00915 | 0.4775
5819523 | 지상 8층 | 지상 8층 | 5819254 | 940 | 0.245 | 0.0094 | 0.48
5819524 | 지상 8층 | 지상 8층 | 5819254 | 650 | 0.1725 | 0.0065 | 0.345
5819529 | 지상 8층 | 지상 8층 | 5819254 | 940 | 0.245 | 0.0094 | 0.48
5819530 | 지상 8층 | 지상 8층 | 5819254 | 915 | 0.23875 | 0.00915 | 0.4775
5819531 | 지상 8층 | 지상 8층 | 5819254 | 915 | 0.23875 | 0.00915 | 0.4775
5819532 | 지상 8층 | 지상 8층 | 5819254 | 940 | 0.245 | 0.0094 | 0.48
5819533 | 지상 8층 | 지상 8층 | 5819254 | 650 | 0.1725 | 0.0065 | 0.345
5819538 | 지상 8층 | 지상 8층 | 5819254 | 940 | 0.245 | 0.0094 | 0.48
5819539 | 지상 8층 | 지상 8층 | 5819254 | 915 | 0.23875 | 0.00915 | 0.4775
5819540 | 지상 8층 | 지상 8층 | 5819254 | 915 | 0.23875 | 0.00915 | 0.4775
5819541 | 지상 8층 | 지상 8층 | 5819254 | 940 | 0.245 | 0.0094 | 0.48
5819542 | 지상 8층 | 지상 8층 | 5819254 | 650 | 0.1725 | 0.0065 | 0.345
5819547 | 지상 8층 | 지상 8층 | 5819254 | 970 | 0.2525 | 0.0097 | 0.495
5819548 | 지상 8층 | 지상 8층 | 5819254 | 945 | 0.24625 | 0.00945 | 0.4925
5819549 | 지상 8층 | 지상 8층 | 5819254 | 945 | 0.24625 | 0.00945 | 0.4925
5819550 | 지상 8층 | 지상 8층 | 5819254 | 940 | 0.245 | 0.0094 | 0.48
5819551 | 지상 8층 | 지상 8층 | 5819254 | 650 | 0.1725 | 0.0065 | 0.345
5819556 | 지상 8층 | 지상 8층 | 5819254 | 1110 | 0.2875 | 0.0111 | 0.565
5819557 | 지상 8층 | 지상 8층 | 5819254 | 1085.02 | 0.281254 | 0.0108502 | 0.562508
5819558 | 지상 8층 | 지상 8층 | 5819254 | 1085.02 | 0.281254 | 0.0108502 | 0.562508
5819559 | 지상 8층 | 지상 8층 | 5819254 | 1080 | 0.28 | 0.0108 | 0.55
5819560 | 지상 8층 | 지상 8층 | 5819254 | 650 | 0.1725 | 0.0065 | 0.345
5819565 | 지상 8층 | 지상 8층 | 5819254 | 940 | 0.245 | 0.0094 | 0.48
5819566 | 지상 8층 | 지상 8층 | 5819254 | 915 | 0.23875 | 0.00915 | 0.4775
5819567 | 지상 8층 | 지상 8층 | 5819254 | 915 | 0.23875 | 0.00915 | 0.4775
5819568 | 지상 8층 | 지상 8층 | 5819254 | 940 | 0.245 | 0.0094 | 0.48
5819569 | 지상 8층 | 지상 8층 | 5819254 | 650 | 0.1725 | 0.0065 | 0.345
5819574 | 지상 8층 | 지상 8층 | 5819254 | 940 | 0.245 | 0.0094 | 0.48
5819575 | 지상 8층 | 지상 8층 | 5819254 | 915 | 0.23875 | 0.00915 | 0.4775
5819576 | 지상 8층 | 지상 8층 | 5819254 | 915 | 0.23875 | 0.00915 | 0.4775
5819577 | 지상 8층 | 지상 8층 | 5819254 | 940 | 0.245 | 0.0094 | 0.48
5819578 | 지상 8층 | 지상 8층 | 5819254 | 650 | 0.1725 | 0.0065 | 0.345
5819583 | 지상 8층 | 지상 8층 | 5819254 | 940 | 0.245 | 0.0094 | 0.48
5819584 | 지상 8층 | 지상 8층 | 5819254 | 915 | 0.23875 | 0.00915 | 0.4775
5819585 | 지상 8층 | 지상 8층 | 5819254 | 915 | 0.23875 | 0.00915 | 0.4775
5819586 | 지상 8층 | 지상 8층 | 5819254 | 940 | 0.245 | 0.0094 | 0.48
5819587 | 지상 8층 | 지상 8층 | 5819254 | 650 | 0.1725 | 0.0065 | 0.345
5819592 | 지상 8층 | 지상 8층 | 5819254 | 940 | 0.245 | 0.0094 | 0.48
5819593 | 지상 8층 | 지상 8층 | 5819254 | 915 | 0.23875 | 0.00915 | 0.4775
5819594 | 지상 8층 | 지상 8층 | 5819254 | 915 | 0.23875 | 0.00915 | 0.4775
5819595 | 지상 8층 | 지상 8층 | 5819254 | 940 | 0.245 | 0.0094 | 0.48
5819596 | 지상 8층 | 지상 8층 | 5819254 | 650 | 0.1725 | 0.0065 | 0.345
5819601 | 지상 8층 | 지상 8층 | 5819254 | 935 | 0.24375 | 0.00935 | 0.4775
5819602 | 지상 8층 | 지상 8층 | 5819254 | 910 | 0.2375 | 0.0091 | 0.475
5819603 | 지상 8층 | 지상 8층 | 5819254 | 910 | 0.2375 | 0.0091 | 0.475
5819604 | 지상 8층 | 지상 8층 | 5819254 | 940 | 0.245 | 0.0094 | 0.48
5819605 | 지상 8층 | 지상 8층 | 5819254 | 650 | 0.1725 | 0.0065 | 0.345
5819610 | 지상 8층 | 지상 8층 | 5819254 | 940 | 0.245 | 0.0094 | 0.48
5819611 | 지상 8층 | 지상 8층 | 5819254 | 915 | 0.23875 | 0.00915 | 0.4775
5819612 | 지상 8층 | 지상 8층 | 5819254 | 915 | 0.23875 | 0.00915 | 0.4775
5819613 | 지상 8층 | 지상 8층 | 5819254 | 995 | 0.25875 | 0.00995 | 0.5075
5819614 | 지상 8층 | 지상 8층 | 5819254 | 650 | 0.1725 | 0.0065 | 0.345
5819619 | 지상 8층 | 지상 8층 | 5819254 | 940 | 0.245 | 0.0094 | 0.48
5819620 | 지상 8층 | 지상 8층 | 5819254 | 915 | 0.23875 | 0.00915 | 0.4775
5819621 | 지상 8층 | 지상 8층 | 5819254 | 915 | 0.23875 | 0.00915 | 0.4775
5819622 | 지상 8층 | 지상 8층 | 5819254 | 940 | 0.245 | 0.0094 | 0.48
5819623 | 지상 8층 | 지상 8층 | 5819254 | 650 | 0.1725 | 0.0065 | 0.345
5819628 | 지상 8층 | 지상 8층 | 5819254 | 940 | 0.245 | 0.0094 | 0.48
5819629 | 지상 8층 | 지상 8층 | 5819254 | 915 | 0.23875 | 0.00915 | 0.4775
5819630 | 지상 8층 | 지상 8층 | 5819254 | 915 | 0.23875 | 0.00915 | 0.4775
5819631 | 지상 8층 | 지상 8층 | 5819254 | 940 | 0.245 | 0.0094 | 0.48
5819632 | 지상 8층 | 지상 8층 | 5819254 | 650 | 0.1725 | 0.0065 | 0.345
5819637 | 지상 8층 | 지상 8층 | 5819254 | 940 | 0.245 | 0.0094 | 0.48
5819638 | 지상 8층 | 지상 8층 | 5819254 | 915 | 0.23875 | 0.00915 | 0.4775
5819639 | 지상 8층 | 지상 8층 | 5819254 | 915 | 0.23875 | 0.00915 | 0.4775
5819640 | 지상 8층 | 지상 8층 | 5819254 | 940 | 0.245 | 0.0094 | 0.48
5819641 | 지상 8층 | 지상 8층 | 5819254 | 650 | 0.1725 | 0.0065 | 0.345
5819644 | 지상 8층 | 지상 8층 | 5819642 | 912.71 | 0.238177 | 0.0091271 | 0.476355
5819645 | 지상 8층 | 지상 8층 | 5819642 | 178.395 | 0.0545986 | 0.00178395 | 0.109197
5819647 | 지상 8층 | 지상 8층 | 5819642 | 1100 | 0.285 | 0.011 | 0.56
5819651 | 지상 8층 | 지상 8층 | 5819642 | 300 | 0.085 | 0.003 | 0.16
5819652 | 지상 8층 | 지상 8층 | 5819642 | 178.395 | 0.0545986 | 0.00178395 | 0.109197
5819656 | 지상 8층 | 지상 8층 | 5819642 | 600 | 0.16 | 0.006 | 0.3
5819657 | 지상 8층 | 지상 8층 | 5819642 | 178.395 | 0.0545986 | 0.00178395 | 0.109197
5819662 | 지상 8층 | 지상 8층 | 5819642 | 178.395 | 0.0545986 | 0.00178395 | 0.109197
5819663 | 지상 8층 | 지상 8층 | 5819642 | 828.5 | 0.217125 | 0.008285 | 0.42425
5819664 | 지상 8층 | 지상 8층 | 5819642 | 803.5 | 0.210875 | 0.008035 | 0.42175
5819665 | 지상 8층 | 지상 8층 | 5819642 | 803.5 | 0.210875 | 0.008035 | 0.42175
5819666 | 지상 8층 | 지상 8층 | 5819642 | 300 | 0.085 | 0.003 | 0.16
5819667 | 지상 8층 | 지상 8층 | 5819642 | 600 | 0.16 | 0.006 | 0.3
5819668 | 지상 8층 | 지상 8층 | 5819642 | 1100 | 0.285 | 0.011 | 0.56
5819673 | 지상 8층 | 지상 8층 | 5819642 | 828.5 | 0.217125 | 0.008285 | 0.42425
5819674 | 지상 8층 | 지상 8층 | 5819642 | 828.5 | 0.217125 | 0.008285 | 0.42425
5819675 | 지상 8층 | 지상 8층 | 5819642 | 803.5 | 0.210875 | 0.008035 | 0.42175
5819676 | 지상 8층 | 지상 8층 | 5819642 | 803.5 | 0.210875 | 0.008035 | 0.42175
5819677 | 지상 8층 | 지상 8층 | 5819642 | 300 | 0.085 | 0.003 | 0.16
5819678 | 지상 8층 | 지상 8층 | 5819642 | 600 | 0.16 | 0.006 | 0.3
5819679 | 지상 8층 | 지상 8층 | 5819642 | 1100 | 0.285 | 0.011 | 0.56
5819684 | 지상 8층 | 지상 8층 | 5819642 | 828.5 | 0.217125 | 0.008285 | 0.42425
5819685 | 지상 8층 | 지상 8층 | 5819642 | 828.5 | 0.217125 | 0.008285 | 0.42425
5819686 | 지상 8층 | 지상 8층 | 5819642 | 803.5 | 0.210875 | 0.008035 | 0.42175
5819687 | 지상 8층 | 지상 8층 | 5819642 | 803.5 | 0.210875 | 0.008035 | 0.42175
5819688 | 지상 8층 | 지상 8층 | 5819642 | 300 | 0.085 | 0.003 | 0.16
5819689 | 지상 8층 | 지상 8층 | 5819642 | 600 | 0.16 | 0.006 | 0.3
5819690 | 지상 8층 | 지상 8층 | 5819642 | 1100 | 0.285 | 0.011 | 0.56
5819695 | 지상 8층 | 지상 8층 | 5819642 | 828.5 | 0.217125 | 0.008285 | 0.42425
5819696 | 지상 8층 | 지상 8층 | 5819642 | 828.5 | 0.217125 | 0.008285 | 0.42425
5819697 | 지상 8층 | 지상 8층 | 5819642 | 803.5 | 0.210875 | 0.008035 | 0.42175
5819698 | 지상 8층 | 지상 8층 | 5819642 | 803.5 | 0.210875 | 0.008035 | 0.42175
5819699 | 지상 8층 | 지상 8층 | 5819642 | 300 | 0.085 | 0.003 | 0.16
5819700 | 지상 8층 | 지상 8층 | 5819642 | 600 | 0.16 | 0.006 | 0.3
5819701 | 지상 8층 | 지상 8층 | 5819642 | 1100 | 0.285 | 0.011 | 0.56
5819706 | 지상 8층 | 지상 8층 | 5819642 | 828.5 | 0.217125 | 0.008285 | 0.42425
5819707 | 지상 8층 | 지상 8층 | 5819642 | 1120 | 0.29 | 0.0112 | 0.58
5819708 | 지상 8층 | 지상 8층 | 5819642 | 1120 | 0.29 | 0.0112 | 0.58
5819709 | 지상 8층 | 지상 8층 | 5819642 | 1120 | 0.29 | 0.0112 | 0.58
5819710 | 지상 8층 | 지상 8층 | 5819642 | 300 | 0.085 | 0.003 | 0.16
5819711 | 지상 8층 | 지상 8층 | 5819642 | 600 | 0.16 | 0.006 | 0.3
5819712 | 지상 8층 | 지상 8층 | 5819642 | 1100 | 0.285 | 0.011 | 0.56
5819717 | 지상 8층 | 지상 8층 | 5819642 | 1120 | 0.29 | 0.0112 | 0.58
5819718 | 지상 8층 | 지상 8층 | 5819642 | 754 | 0.1985 | 0.00754 | 0.387
5819719 | 지상 8층 | 지상 8층 | 5819642 | 729 | 0.19225 | 0.00729 | 0.3845
5819720 | 지상 8층 | 지상 8층 | 5819642 | 729 | 0.19225 | 0.00729 | 0.3845
5819721 | 지상 8층 | 지상 8층 | 5819642 | 300 | 0.085 | 0.003 | 0.16
5819722 | 지상 8층 | 지상 8층 | 5819642 | 600 | 0.16 | 0.006 | 0.3
5819723 | 지상 8층 | 지상 8층 | 5819642 | 1100 | 0.285 | 0.011 | 0.56
5819728 | 지상 8층 | 지상 8층 | 5819642 | 754 | 0.1985 | 0.00754 | 0.387
5819729 | 지상 8층 | 지상 8층 | 5819642 | 754 | 0.1985 | 0.00754 | 0.387
5819730 | 지상 8층 | 지상 8층 | 5819642 | 729 | 0.19225 | 0.00729 | 0.3845
5819731 | 지상 8층 | 지상 8층 | 5819642 | 729 | 0.19225 | 0.00729 | 0.3845
5819732 | 지상 8층 | 지상 8층 | 5819642 | 300 | 0.085 | 0.003 | 0.16
5819733 | 지상 8층 | 지상 8층 | 5819642 | 600 | 0.16 | 0.006 | 0.3
5819734 | 지상 8층 | 지상 8층 | 5819642 | 1100 | 0.285 | 0.011 | 0.56
5819739 | 지상 8층 | 지상 8층 | 5819642 | 754 | 0.1985 | 0.00754 | 0.387
5819740 | 지상 8층 | 지상 8층 | 5819642 | 754 | 0.1985 | 0.00754 | 0.387
5819741 | 지상 8층 | 지상 8층 | 5819642 | 729 | 0.19225 | 0.00729 | 0.3845
5819742 | 지상 8층 | 지상 8층 | 5819642 | 729 | 0.19225 | 0.00729 | 0.3845
5819743 | 지상 8층 | 지상 8층 | 5819642 | 300 | 0.085 | 0.003 | 0.16
5819744 | 지상 8층 | 지상 8층 | 5819642 | 600 | 0.16 | 0.006 | 0.3
5819745 | 지상 8층 | 지상 8층 | 5819642 | 1100 | 0.285 | 0.011 | 0.56
5819750 | 지상 8층 | 지상 8층 | 5819642 | 754 | 0.1985 | 0.00754 | 0.387
5819751 | 지상 8층 | 지상 8층 | 5819642 | 754 | 0.1985 | 0.00754 | 0.387
5819752 | 지상 8층 | 지상 8층 | 5819642 | 729 | 0.19225 | 0.00729 | 0.3845
5819753 | 지상 8층 | 지상 8층 | 5819642 | 729 | 0.19225 | 0.00729 | 0.3845
5819754 | 지상 8층 | 지상 8층 | 5819642 | 300 | 0.085 | 0.003 | 0.16
5819755 | 지상 8층 | 지상 8층 | 5819642 | 600 | 0.16 | 0.006 | 0.3
5819756 | 지상 8층 | 지상 8층 | 5819642 | 1100 | 0.285 | 0.011 | 0.56
5819761 | 지상 8층 | 지상 8층 | 5819642 | 754 | 0.1985 | 0.00754 | 0.387
5819762 | 지상 8층 | 지상 8층 | 5819642 | 1120 | 0.29 | 0.0112 | 0.58
5819763 | 지상 8층 | 지상 8층 | 5819642 | 1120 | 0.29 | 0.0112 | 0.58
5819764 | 지상 8층 | 지상 8층 | 5819642 | 1120 | 0.29 | 0.0112 | 0.58
5819765 | 지상 8층 | 지상 8층 | 5819642 | 300 | 0.085 | 0.003 | 0.16
5819766 | 지상 8층 | 지상 8층 | 5819642 | 600 | 0.16 | 0.006 | 0.3
5819767 | 지상 8층 | 지상 8층 | 5819642 | 1100 | 0.285 | 0.011 | 0.56
5819772 | 지상 8층 | 지상 8층 | 5819642 | 1120 | 0.29 | 0.0112 | 0.58
5819773 | 지상 8층 | 지상 8층 | 5819642 | 741.5 | 0.195375 | 0.007415 | 0.38075
5819774 | 지상 8층 | 지상 8층 | 5819642 | 716.5 | 0.189125 | 0.007165 | 0.37825
5819775 | 지상 8층 | 지상 8층 | 5819642 | 716.5 | 0.189125 | 0.007165 | 0.37825
5819776 | 지상 8층 | 지상 8층 | 5819642 | 300 | 0.085 | 0.003 | 0.16
5819777 | 지상 8층 | 지상 8층 | 5819642 | 600 | 0.16 | 0.006 | 0.3
5819778 | 지상 8층 | 지상 8층 | 5819642 | 1100 | 0.285 | 0.011 | 0.56
5819783 | 지상 8층 | 지상 8층 | 5819642 | 741.5 | 0.195375 | 0.007415 | 0.38075
5819784 | 지상 8층 | 지상 8층 | 5819642 | 741.5 | 0.195375 | 0.007415 | 0.38075
5819785 | 지상 8층 | 지상 8층 | 5819642 | 716.5 | 0.189125 | 0.007165 | 0.37825
5819786 | 지상 8층 | 지상 8층 | 5819642 | 716.5 | 0.189125 | 0.007165 | 0.37825
5819787 | 지상 8층 | 지상 8층 | 5819642 | 300 | 0.085 | 0.003 | 0.16
5819788 | 지상 8층 | 지상 8층 | 5819642 | 600 | 0.16 | 0.006 | 0.3
5819789 | 지상 8층 | 지상 8층 | 5819642 | 1100 | 0.285 | 0.011 | 0.56
5819794 | 지상 8층 | 지상 8층 | 5819642 | 741.5 | 0.195375 | 0.007415 | 0.38075
5819795 | 지상 8층 | 지상 8층 | 5819642 | 741.5 | 0.195375 | 0.007415 | 0.38075
5819796 | 지상 8층 | 지상 8층 | 5819642 | 716.5 | 0.189125 | 0.007165 | 0.37825
5819797 | 지상 8층 | 지상 8층 | 5819642 | 716.5 | 0.189125 | 0.007165 | 0.37825
5819798 | 지상 8층 | 지상 8층 | 5819642 | 300 | 0.085 | 0.003 | 0.16
5819799 | 지상 8층 | 지상 8층 | 5819642 | 600 | 0.16 | 0.006 | 0.3
5819800 | 지상 8층 | 지상 8층 | 5819642 | 1100 | 0.285 | 0.011 | 0.56
5819805 | 지상 8층 | 지상 8층 | 5819642 | 741.5 | 0.195375 | 0.007415 | 0.38075
5819806 | 지상 8층 | 지상 8층 | 5819642 | 741.5 | 0.195375 | 0.007415 | 0.38075
5819807 | 지상 8층 | 지상 8층 | 5819642 | 716.5 | 0.189125 | 0.007165 | 0.37825
5819808 | 지상 8층 | 지상 8층 | 5819642 | 716.5 | 0.189125 | 0.007165 | 0.37825
5819809 | 지상 8층 | 지상 8층 | 5819642 | 300 | 0.085 | 0.003 | 0.16
5819810 | 지상 8층 | 지상 8층 | 5819642 | 600 | 0.16 | 0.006 | 0.3
5819811 | 지상 8층 | 지상 8층 | 5819642 | 1100 | 0.285 | 0.011 | 0.56
5819816 | 지상 8층 | 지상 8층 | 5819642 | 741.5 | 0.195375 | 0.007415 | 0.38075
5819817 | 지상 8층 | 지상 8층 | 5819642 | 1120 | 0.29 | 0.0112 | 0.58
5819818 | 지상 8층 | 지상 8층 | 5819642 | 1120 | 0.29 | 0.0112 | 0.58
5819819 | 지상 8층 | 지상 8층 | 5819642 | 1120 | 0.29 | 0.0112 | 0.58
5819820 | 지상 8층 | 지상 8층 | 5819642 | 300 | 0.085 | 0.003 | 0.16
5819821 | 지상 8층 | 지상 8층 | 5819642 | 600 | 0.16 | 0.006 | 0.3
5819822 | 지상 8층 | 지상 8층 | 5819642 | 1100 | 0.285 | 0.011 | 0.56
5819827 | 지상 8층 | 지상 8층 | 5819642 | 1120 | 0.29 | 0.0112 | 0.58
5819828 | 지상 8층 | 지상 8층 | 5819642 | 743.357 | 0.195839 | 0.00743357 | 0.381679
5819829 | 지상 8층 | 지상 8층 | 5819642 | 718.357 | 0.189589 | 0.00718357 | 0.379179
5819830 | 지상 8층 | 지상 8층 | 5819642 | 718.357 | 0.189589 | 0.00718357 | 0.379179
5819831 | 지상 8층 | 지상 8층 | 5819642 | 300 | 0.085 | 0.003 | 0.16
5819832 | 지상 8층 | 지상 8층 | 5819642 | 600 | 0.16 | 0.006 | 0.3
5819833 | 지상 8층 | 지상 8층 | 5819642 | 1100 | 0.285 | 0.011 | 0.56
5819838 | 지상 8층 | 지상 8층 | 5819642 | 743.357 | 0.195839 | 0.00743357 | 0.381679
5819839 | 지상 8층 | 지상 8층 | 5819642 | 743.357 | 0.195839 | 0.00743357 | 0.381679
5819840 | 지상 8층 | 지상 8층 | 5819642 | 718.357 | 0.189589 | 0.00718357 | 0.379179
5819841 | 지상 8층 | 지상 8층 | 5819642 | 718.357 | 0.189589 | 0.00718357 | 0.379179
5819842 | 지상 8층 | 지상 8층 | 5819642 | 300 | 0.085 | 0.003 | 0.16
5819843 | 지상 8층 | 지상 8층 | 5819642 | 600 | 0.16 | 0.006 | 0.3
5819844 | 지상 8층 | 지상 8층 | 5819642 | 1100 | 0.285 | 0.011 | 0.56
5819849 | 지상 8층 | 지상 8층 | 5819642 | 743.357 | 0.195839 | 0.00743357 | 0.381679
5819850 | 지상 8층 | 지상 8층 | 5819642 | 743.357 | 0.195839 | 0.00743357 | 0.381679
5819851 | 지상 8층 | 지상 8층 | 5819642 | 718.357 | 0.189589 | 0.00718357 | 0.379179
5819852 | 지상 8층 | 지상 8층 | 5819642 | 718.357 | 0.189589 | 0.00718357 | 0.379179
5819853 | 지상 8층 | 지상 8층 | 5819642 | 300 | 0.085 | 0.003 | 0.16
5819854 | 지상 8층 | 지상 8층 | 5819642 | 600 | 0.16 | 0.006 | 0.3
5819855 | 지상 8층 | 지상 8층 | 5819642 | 1100 | 0.285 | 0.011 | 0.56
5819860 | 지상 8층 | 지상 8층 | 5819642 | 743.357 | 0.195839 | 0.00743357 | 0.381679
5819861 | 지상 8층 | 지상 8층 | 5819642 | 743.357 | 0.195839 | 0.00743357 | 0.381679
5819862 | 지상 8층 | 지상 8층 | 5819642 | 718.357 | 0.189589 | 0.00718357 | 0.379179
5819863 | 지상 8층 | 지상 8층 | 5819642 | 718.357 | 0.189589 | 0.00718357 | 0.379179
5819864 | 지상 8층 | 지상 8층 | 5819642 | 300 | 0.085 | 0.003 | 0.16
5819865 | 지상 8층 | 지상 8층 | 5819642 | 600 | 0.16 | 0.006 | 0.3
5819866 | 지상 8층 | 지상 8층 | 5819642 | 1100 | 0.285 | 0.011 | 0.56
5819871 | 지상 8층 | 지상 8층 | 5819642 | 743.357 | 0.195839 | 0.00743357 | 0.381679
5819872 | 지상 8층 | 지상 8층 | 5819642 | 743.357 | 0.195839 | 0.00743357 | 0.381679
5819873 | 지상 8층 | 지상 8층 | 5819642 | 718.357 | 0.189589 | 0.00718357 | 0.379179
5819874 | 지상 8층 | 지상 8층 | 5819642 | 718.357 | 0.189589 | 0.00718357 | 0.379179
5819875 | 지상 8층 | 지상 8층 | 5819642 | 300 | 0.085 | 0.003 | 0.16
5819876 | 지상 8층 | 지상 8층 | 5819642 | 600 | 0.16 | 0.006 | 0.3
5819877 | 지상 8층 | 지상 8층 | 5819642 | 1100 | 0.285 | 0.011 | 0.56
5819882 | 지상 8층 | 지상 8층 | 5819642 | 743.357 | 0.195839 | 0.00743357 | 0.381679
5819883 | 지상 8층 | 지상 8층 | 5819642 | 743.357 | 0.195839 | 0.00743357 | 0.381679
5819884 | 지상 8층 | 지상 8층 | 5819642 | 718.357 | 0.189589 | 0.00718357 | 0.379179
5819885 | 지상 8층 | 지상 8층 | 5819642 | 718.357 | 0.189589 | 0.00718357 | 0.379179
5819886 | 지상 8층 | 지상 8층 | 5819642 | 300 | 0.085 | 0.003 | 0.16
5819887 | 지상 8층 | 지상 8층 | 5819642 | 600 | 0.16 | 0.006 | 0.3
5819888 | 지상 8층 | 지상 8층 | 5819642 | 1100 | 0.285 | 0.011 | 0.56
5819893 | 지상 8층 | 지상 8층 | 5819642 | 743.357 | 0.195839 | 0.00743357 | 0.381679
5819894 | 지상 8층 | 지상 8층 | 5819642 | 743.357 | 0.195839 | 0.00743357 | 0.381679
5819895 | 지상 8층 | 지상 8층 | 5819642 | 718.357 | 0.189589 | 0.00718357 | 0.379179
5819896 | 지상 8층 | 지상 8층 | 5819642 | 718.357 | 0.189589 | 0.00718357 | 0.379179
5819897 | 지상 8층 | 지상 8층 | 5819642 | 300 | 0.085 | 0.003 | 0.16
5819898 | 지상 8층 | 지상 8층 | 5819642 | 600 | 0.16 | 0.006 | 0.3
5819899 | 지상 8층 | 지상 8층 | 5819642 | 1100 | 0.285 | 0.011 | 0.56
5819904 | 지상 8층 | 지상 8층 | 5819642 | 743.357 | 0.195839 | 0.00743357 | 0.381679
5819905 | 지상 8층 | 지상 8층 | 5819642 | 912.71 | 0.238177 | 0.0091271 | 0.476355
5819906 | 지상 8층 | 지상 8층 | 5819642 | 912.71 | 0.238177 | 0.0091271 | 0.476355
5819907 | 지상 8층 | 지상 8층 | 5819642 | 912.71 | 0.238177 | 0.0091271 | 0.476355
5819908 | 지상 8층 | 지상 8층 | 5819642 | 300 | 0.085 | 0.003 | 0.16
5819909 | 지상 8층 | 지상 8층 | 5819642 | 600 | 0.16 | 0.006 | 0.3
5819910 | 지상 8층 | 지상 8층 | 5819642 | 1100 | 0.285 | 0.011 | 0.56
5819915 | 지상 8층 | 지상 8층 | 5819642 | 828.5 | 0.217125 | 0.008285 | 0.42425
5819916 | 지상 8층 | 지상 8층 | 5819642 | 828.5 | 0.217125 | 0.008285 | 0.42425
5819917 | 지상 8층 | 지상 8층 | 5819642 | 803.5 | 0.210875 | 0.008035 | 0.42175
5819918 | 지상 8층 | 지상 8층 | 5819642 | 803.5 | 0.210875 | 0.008035 | 0.42175
5819919 | 지상 8층 | 지상 8층 | 5819642 | 650 | 0.1725 | 0.0065 | 0.345
5819924 | 지상 8층 | 지상 8층 | 5819642 | 828.5 | 0.217125 | 0.008285 | 0.42425
5819925 | 지상 8층 | 지상 8층 | 5819642 | 828.5 | 0.217125 | 0.008285 | 0.42425
5819926 | 지상 8층 | 지상 8층 | 5819642 | 803.5 | 0.210875 | 0.008035 | 0.42175
5819927 | 지상 8층 | 지상 8층 | 5819642 | 803.5 | 0.210875 | 0.008035 | 0.42175
5819928 | 지상 8층 | 지상 8층 | 5819642 | 650 | 0.1725 | 0.0065 | 0.345
5819933 | 지상 8층 | 지상 8층 | 5819642 | 828.5 | 0.217125 | 0.008285 | 0.42425
5819934 | 지상 8층 | 지상 8층 | 5819642 | 828.5 | 0.217125 | 0.008285 | 0.42425
5819935 | 지상 8층 | 지상 8층 | 5819642 | 803.5 | 0.210875 | 0.008035 | 0.42175
5819936 | 지상 8층 | 지상 8층 | 5819642 | 803.5 | 0.210875 | 0.008035 | 0.42175
5819937 | 지상 8층 | 지상 8층 | 5819642 | 650 | 0.1725 | 0.0065 | 0.345
5819942 | 지상 8층 | 지상 8층 | 5819642 | 828.5 | 0.217125 | 0.008285 | 0.42425
5819943 | 지상 8층 | 지상 8층 | 5819642 | 828.5 | 0.217125 | 0.008285 | 0.42425
5819944 | 지상 8층 | 지상 8층 | 5819642 | 803.5 | 0.210875 | 0.008035 | 0.42175
5819945 | 지상 8층 | 지상 8층 | 5819642 | 803.5 | 0.210875 | 0.008035 | 0.42175
5819946 | 지상 8층 | 지상 8층 | 5819642 | 650 | 0.1725 | 0.0065 | 0.345
5819951 | 지상 8층 | 지상 8층 | 5819642 | 754 | 0.1985 | 0.00754 | 0.387
5819952 | 지상 8층 | 지상 8층 | 5819642 | 754 | 0.1985 | 0.00754 | 0.387
5819953 | 지상 8층 | 지상 8층 | 5819642 | 729 | 0.19225 | 0.00729 | 0.3845
5819954 | 지상 8층 | 지상 8층 | 5819642 | 729 | 0.19225 | 0.00729 | 0.3845
5819955 | 지상 8층 | 지상 8층 | 5819642 | 650 | 0.1725 | 0.0065 | 0.345
5819960 | 지상 8층 | 지상 8층 | 5819642 | 754 | 0.1985 | 0.00754 | 0.387
5819961 | 지상 8층 | 지상 8층 | 5819642 | 754 | 0.1985 | 0.00754 | 0.387
5819962 | 지상 8층 | 지상 8층 | 5819642 | 729 | 0.19225 | 0.00729 | 0.3845
5819963 | 지상 8층 | 지상 8층 | 5819642 | 729 | 0.19225 | 0.00729 | 0.3845
5819964 | 지상 8층 | 지상 8층 | 5819642 | 650 | 0.1725 | 0.0065 | 0.345
5819969 | 지상 8층 | 지상 8층 | 5819642 | 754 | 0.1985 | 0.00754 | 0.387
5819970 | 지상 8층 | 지상 8층 | 5819642 | 754 | 0.1985 | 0.00754 | 0.387
5819971 | 지상 8층 | 지상 8층 | 5819642 | 729 | 0.19225 | 0.00729 | 0.3845
5819972 | 지상 8층 | 지상 8층 | 5819642 | 729 | 0.19225 | 0.00729 | 0.3845
5819973 | 지상 8층 | 지상 8층 | 5819642 | 650 | 0.1725 | 0.0065 | 0.345
5819978 | 지상 8층 | 지상 8층 | 5819642 | 754 | 0.1985 | 0.00754 | 0.387
5819979 | 지상 8층 | 지상 8층 | 5819642 | 754 | 0.1985 | 0.00754 | 0.387
5819980 | 지상 8층 | 지상 8층 | 5819642 | 729 | 0.19225 | 0.00729 | 0.3845
5819981 | 지상 8층 | 지상 8층 | 5819642 | 729 | 0.19225 | 0.00729 | 0.3845
5819982 | 지상 8층 | 지상 8층 | 5819642 | 650 | 0.1725 | 0.0065 | 0.345
5819987 | 지상 8층 | 지상 8층 | 5819642 | 741.5 | 0.195375 | 0.007415 | 0.38075
5819988 | 지상 8층 | 지상 8층 | 5819642 | 741.5 | 0.195375 | 0.007415 | 0.38075
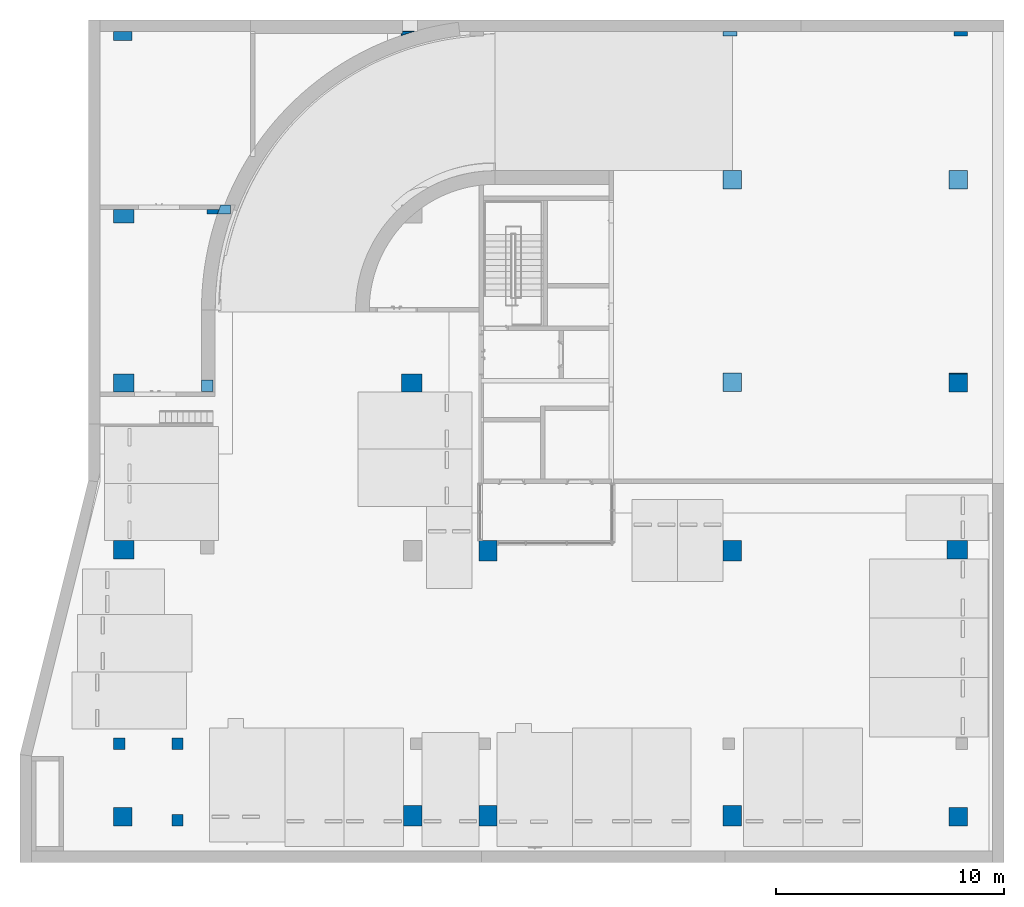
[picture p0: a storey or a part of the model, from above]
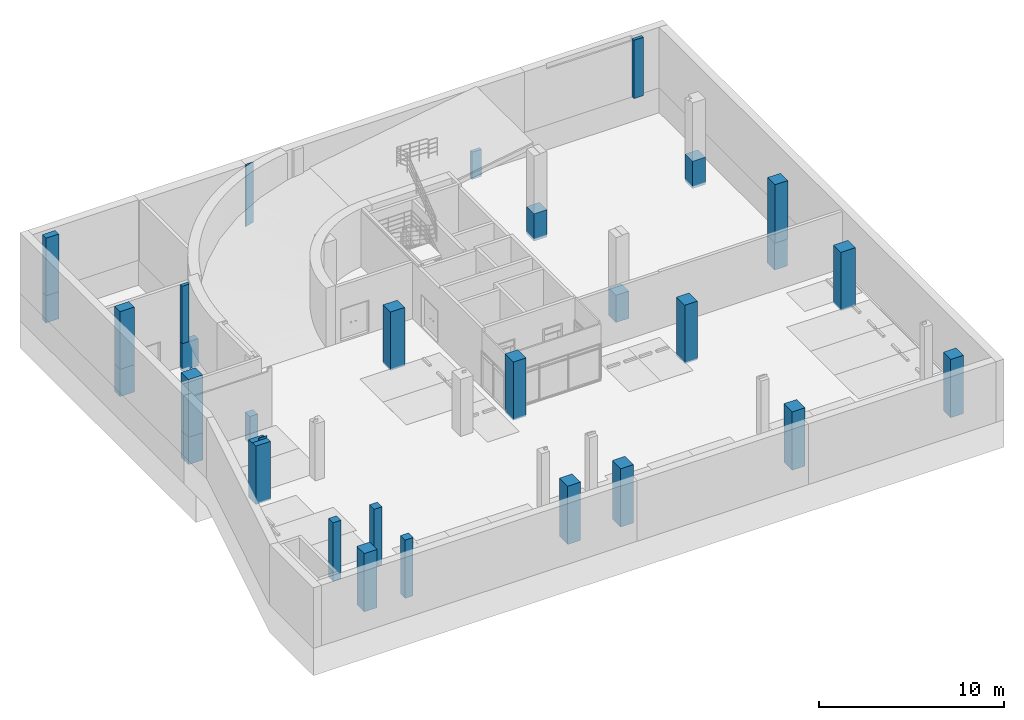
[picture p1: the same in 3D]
Properties of the parts of a building model (IFC2X3), part 22 of 39

# IfcMember: 직사각형 멀리언:CW200-직사각형 멀리언 50x200mm (8700)
Name (직사각형 멀리언:CW200-직사각형 멀리언 50x200mm:...) | In | 레벨 | 호스트 ID | 길이 (mm) = Span (mm) | 면적 (m2) = CrossSectionArea (m2) | 체적 (m3) = NetVolume (m3) | NetSurfaceArea (m2)
5819989 | 지상 8층 | 지상 8층 | 5819642 | 716.5 | 0.189125 | 0.007165 | 0.37825
5819990 | 지상 8층 | 지상 8층 | 5819642 | 716.5 | 0.189125 | 0.007165 | 0.37825
5819991 | 지상 8층 | 지상 8층 | 5819642 | 650 | 0.1725 | 0.0065 | 0.345
5819996 | 지상 8층 | 지상 8층 | 5819642 | 741.5 | 0.195375 | 0.007415 | 0.38075
5819997 | 지상 8층 | 지상 8층 | 5819642 | 741.5 | 0.195375 | 0.007415 | 0.38075
5819998 | 지상 8층 | 지상 8층 | 5819642 | 716.5 | 0.189125 | 0.007165 | 0.37825
5819999 | 지상 8층 | 지상 8층 | 5819642 | 716.5 | 0.189125 | 0.007165 | 0.37825
5820000 | 지상 8층 | 지상 8층 | 5819642 | 650 | 0.1725 | 0.0065 | 0.345
5820005 | 지상 8층 | 지상 8층 | 5819642 | 741.5 | 0.195375 | 0.007415 | 0.38075
5820006 | 지상 8층 | 지상 8층 | 5819642 | 741.5 | 0.195375 | 0.007415 | 0.38075
5820007 | 지상 8층 | 지상 8층 | 5819642 | 716.5 | 0.189125 | 0.007165 | 0.37825
5820008 | 지상 8층 | 지상 8층 | 5819642 | 716.5 | 0.189125 | 0.007165 | 0.37825
5820009 | 지상 8층 | 지상 8층 | 5819642 | 650 | 0.1725 | 0.0065 | 0.345
5820014 | 지상 8층 | 지상 8층 | 5819642 | 741.5 | 0.195375 | 0.007415 | 0.38075
5820015 | 지상 8층 | 지상 8층 | 5819642 | 741.5 | 0.195375 | 0.007415 | 0.38075
5820016 | 지상 8층 | 지상 8층 | 5819642 | 716.5 | 0.189125 | 0.007165 | 0.37825
5820017 | 지상 8층 | 지상 8층 | 5819642 | 716.5 | 0.189125 | 0.007165 | 0.37825
5820018 | 지상 8층 | 지상 8층 | 5819642 | 650 | 0.1725 | 0.0065 | 0.345
5820023 | 지상 8층 | 지상 8층 | 5819642 | 743.357 | 0.195839 | 0.00743357 | 0.381679
5820024 | 지상 8층 | 지상 8층 | 5819642 | 743.357 | 0.195839 | 0.00743357 | 0.381679
5820025 | 지상 8층 | 지상 8층 | 5819642 | 718.357 | 0.189589 | 0.00718357 | 0.379179
5820026 | 지상 8층 | 지상 8층 | 5819642 | 718.357 | 0.189589 | 0.00718357 | 0.379179
5820027 | 지상 8층 | 지상 8층 | 5819642 | 650 | 0.1725 | 0.0065 | 0.345
5820032 | 지상 8층 | 지상 8층 | 5819642 | 743.357 | 0.195839 | 0.00743357 | 0.381679
5820033 | 지상 8층 | 지상 8층 | 5819642 | 743.357 | 0.195839 | 0.00743357 | 0.381679
5820034 | 지상 8층 | 지상 8층 | 5819642 | 718.357 | 0.189589 | 0.00718357 | 0.379179
5820035 | 지상 8층 | 지상 8층 | 5819642 | 718.357 | 0.189589 | 0.00718357 | 0.379179
5820036 | 지상 8층 | 지상 8층 | 5819642 | 650 | 0.1725 | 0.0065 | 0.345
5820041 | 지상 8층 | 지상 8층 | 5819642 | 743.357 | 0.195839 | 0.00743357 | 0.381679
5820042 | 지상 8층 | 지상 8층 | 5819642 | 743.357 | 0.195839 | 0.00743357 | 0.381679
5820043 | 지상 8층 | 지상 8층 | 5819642 | 718.357 | 0.189589 | 0.00718357 | 0.379179
5820044 | 지상 8층 | 지상 8층 | 5819642 | 718.357 | 0.189589 | 0.00718357 | 0.379179
5820045 | 지상 8층 | 지상 8층 | 5819642 | 650 | 0.1725 | 0.0065 | 0.345
5820050 | 지상 8층 | 지상 8층 | 5819642 | 743.357 | 0.195839 | 0.00743357 | 0.381679
5820051 | 지상 8층 | 지상 8층 | 5819642 | 743.357 | 0.195839 | 0.00743357 | 0.381679
5820052 | 지상 8층 | 지상 8층 | 5819642 | 718.357 | 0.189589 | 0.00718357 | 0.379179
5820053 | 지상 8층 | 지상 8층 | 5819642 | 718.357 | 0.189589 | 0.00718357 | 0.379179
5820054 | 지상 8층 | 지상 8층 | 5819642 | 650 | 0.1725 | 0.0065 | 0.345
5820059 | 지상 8층 | 지상 8층 | 5819642 | 743.357 | 0.195839 | 0.00743357 | 0.381679
5820060 | 지상 8층 | 지상 8층 | 5819642 | 743.357 | 0.195839 | 0.00743357 | 0.381679
5820061 | 지상 8층 | 지상 8층 | 5819642 | 718.357 | 0.189589 | 0.00718357 | 0.379179
5820062 | 지상 8층 | 지상 8층 | 5819642 | 718.357 | 0.189589 | 0.00718357 | 0.379179
5820063 | 지상 8층 | 지상 8층 | 5819642 | 650 | 0.1725 | 0.0065 | 0.345
5820068 | 지상 8층 | 지상 8층 | 5819642 | 743.357 | 0.195839 | 0.00743357 | 0.381679
5820069 | 지상 8층 | 지상 8층 | 5819642 | 743.357 | 0.195839 | 0.00743357 | 0.381679
5820070 | 지상 8층 | 지상 8층 | 5819642 | 718.357 | 0.189589 | 0.00718357 | 0.379179
5820071 | 지상 8층 | 지상 8층 | 5819642 | 718.357 | 0.189589 | 0.00718357 | 0.379179
5820072 | 지상 8층 | 지상 8층 | 5819642 | 650 | 0.1725 | 0.0065 | 0.345
5820077 | 지상 8층 | 지상 8층 | 5819642 | 743.357 | 0.195839 | 0.00743357 | 0.381679
5820078 | 지상 8층 | 지상 8층 | 5819642 | 743.357 | 0.195839 | 0.00743357 | 0.381679
5820079 | 지상 8층 | 지상 8층 | 5819642 | 718.357 | 0.189589 | 0.00718357 | 0.379179
5820080 | 지상 8층 | 지상 8층 | 5819642 | 718.357 | 0.189589 | 0.00718357 | 0.379179
5820081 | 지상 8층 | 지상 8층 | 5819642 | 650 | 0.1725 | 0.0065 | 0.345
5820123 | 지상 7층 | 지상 7층 | 5820121 | 892.184 | 0.233046 | 0.00892184 | 0.466092
5820124 | 지상 7층 | 지상 7층 | 5820121 | 912.816 | 0.238204 | 0.00912816 | 0.476408
5820129 | 지상 7층 | 지상 7층 | 5820121 | 912.816 | 0.238204 | 0.00912816 | 0.476408
5820133 | 지상 7층 | 지상 7층 | 5820121 | 912.816 | 0.238204 | 0.00912816 | 0.476408
5820138 | 지상 7층 | 지상 7층 | 5820121 | 912.816 | 0.238204 | 0.00912816 | 0.476408
5820139 | 지상 7층 | 지상 7층 | 5820121 | 970 | 0.2525 | 0.0097 | 0.495
5820140 | 지상 7층 | 지상 7층 | 5820121 | 945 | 0.24625 | 0.00945 | 0.4925
5820141 | 지상 7층 | 지상 7층 | 5820121 | 945 | 0.24625 | 0.00945 | 0.4925
5820142 | 지상 7층 | 지상 7층 | 5820121 | 300 | 0.085 | 0.003 | 0.16
5820143 | 지상 7층 | 지상 7층 | 5820121 | 600 | 0.16 | 0.006 | 0.3
5820144 | 지상 7층 | 지상 7층 | 5820121 | 1100 | 0.285 | 0.011 | 0.56
5820149 | 지상 7층 | 지상 7층 | 5820121 | 940 | 0.245 | 0.0094 | 0.48
5820150 | 지상 7층 | 지상 7층 | 5820121 | 940 | 0.245 | 0.0094 | 0.48
5820151 | 지상 7층 | 지상 7층 | 5820121 | 915 | 0.23875 | 0.00915 | 0.4775
5820152 | 지상 7층 | 지상 7층 | 5820121 | 915 | 0.23875 | 0.00915 | 0.4775
5820153 | 지상 7층 | 지상 7층 | 5820121 | 300 | 0.085 | 0.003 | 0.16
5820154 | 지상 7층 | 지상 7층 | 5820121 | 600 | 0.16 | 0.006 | 0.3
5820155 | 지상 7층 | 지상 7층 | 5820121 | 1100 | 0.285 | 0.011 | 0.56
5820160 | 지상 7층 | 지상 7층 | 5820121 | 940 | 0.245 | 0.0094 | 0.48
5820161 | 지상 7층 | 지상 7층 | 5820121 | 940 | 0.245 | 0.0094 | 0.48
5820162 | 지상 7층 | 지상 7층 | 5820121 | 915 | 0.23875 | 0.00915 | 0.4775
5820163 | 지상 7층 | 지상 7층 | 5820121 | 915 | 0.23875 | 0.00915 | 0.4775
5820164 | 지상 7층 | 지상 7층 | 5820121 | 300 | 0.085 | 0.003 | 0.16
5820165 | 지상 7층 | 지상 7층 | 5820121 | 600 | 0.16 | 0.006 | 0.3
5820166 | 지상 7층 | 지상 7층 | 5820121 | 1100 | 0.285 | 0.011 | 0.56
5820171 | 지상 7층 | 지상 7층 | 5820121 | 940 | 0.245 | 0.0094 | 0.48
5820172 | 지상 7층 | 지상 7층 | 5820121 | 940 | 0.245 | 0.0094 | 0.48
5820173 | 지상 7층 | 지상 7층 | 5820121 | 915 | 0.23875 | 0.00915 | 0.4775
5820174 | 지상 7층 | 지상 7층 | 5820121 | 915 | 0.23875 | 0.00915 | 0.4775
5820175 | 지상 7층 | 지상 7층 | 5820121 | 300 | 0.085 | 0.003 | 0.16
5820176 | 지상 7층 | 지상 7층 | 5820121 | 600 | 0.16 | 0.006 | 0.3
5820177 | 지상 7층 | 지상 7층 | 5820121 | 1100 | 0.285 | 0.011 | 0.56
5820182 | 지상 7층 | 지상 7층 | 5820121 | 940 | 0.245 | 0.0094 | 0.48
5820183 | 지상 7층 | 지상 7층 | 5820121 | 940 | 0.245 | 0.0094 | 0.48
5820184 | 지상 7층 | 지상 7층 | 5820121 | 915 | 0.23875 | 0.00915 | 0.4775
5820185 | 지상 7층 | 지상 7층 | 5820121 | 915 | 0.23875 | 0.00915 | 0.4775
5820186 | 지상 7층 | 지상 7층 | 5820121 | 300 | 0.085 | 0.003 | 0.16
5820187 | 지상 7층 | 지상 7층 | 5820121 | 600 | 0.16 | 0.006 | 0.3
5820188 | 지상 7층 | 지상 7층 | 5820121 | 1100 | 0.285 | 0.011 | 0.56
5820193 | 지상 7층 | 지상 7층 | 5820121 | 940 | 0.245 | 0.0094 | 0.48
5820194 | 지상 7층 | 지상 7층 | 5820121 | 940 | 0.245 | 0.0094 | 0.48
5820195 | 지상 7층 | 지상 7층 | 5820121 | 915 | 0.23875 | 0.00915 | 0.4775
5820196 | 지상 7층 | 지상 7층 | 5820121 | 915 | 0.23875 | 0.00915 | 0.4775
5820197 | 지상 7층 | 지상 7층 | 5820121 | 300 | 0.085 | 0.003 | 0.16
5820198 | 지상 7층 | 지상 7층 | 5820121 | 600 | 0.16 | 0.006 | 0.3
5820199 | 지상 7층 | 지상 7층 | 5820121 | 1100 | 0.285 | 0.011 | 0.56
5820204 | 지상 7층 | 지상 7층 | 5820121 | 970 | 0.2525 | 0.0097 | 0.495
5820205 | 지상 7층 | 지상 7층 | 5820121 | 1010 | 0.2625 | 0.0101 | 0.525
5820206 | 지상 7층 | 지상 7층 | 5820121 | 1010 | 0.2625 | 0.0101 | 0.525
5820207 | 지상 7층 | 지상 7층 | 5820121 | 1010 | 0.2625 | 0.0101 | 0.525
5820208 | 지상 7층 | 지상 7층 | 5820121 | 300 | 0.085 | 0.003 | 0.16
5820209 | 지상 7층 | 지상 7층 | 5820121 | 600 | 0.16 | 0.006 | 0.3
5820210 | 지상 7층 | 지상 7층 | 5820121 | 1100 | 0.285 | 0.011 | 0.56
5820215 | 지상 7층 | 지상 7층 | 5820121 | 1010 | 0.2625 | 0.0101 | 0.525
5820216 | 지상 7층 | 지상 7층 | 5820121 | 1080 | 0.28 | 0.0108 | 0.55
5820217 | 지상 7층 | 지상 7층 | 5820121 | 1055 | 0.27375 | 0.01055 | 0.5475
5820218 | 지상 7층 | 지상 7층 | 5820121 | 1055 | 0.27375 | 0.01055 | 0.5475
5820219 | 지상 7층 | 지상 7층 | 5820121 | 300 | 0.085 | 0.003 | 0.16
5820220 | 지상 7층 | 지상 7층 | 5820121 | 600 | 0.16 | 0.006 | 0.3
5820221 | 지상 7층 | 지상 7층 | 5820121 | 1100 | 0.285 | 0.011 | 0.56
5820226 | 지상 7층 | 지상 7층 | 5820121 | 1110 | 0.2875 | 0.0111 | 0.565
5820227 | 지상 7층 | 지상 7층 | 5820121 | 1010 | 0.2625 | 0.0101 | 0.525
5820228 | 지상 7층 | 지상 7층 | 5820121 | 1010 | 0.2625 | 0.0101 | 0.525
5820229 | 지상 7층 | 지상 7층 | 5820121 | 1010 | 0.2625 | 0.0101 | 0.525
5820230 | 지상 7층 | 지상 7층 | 5820121 | 300 | 0.085 | 0.003 | 0.16
5820231 | 지상 7층 | 지상 7층 | 5820121 | 600 | 0.16 | 0.006 | 0.3
5820232 | 지상 7층 | 지상 7층 | 5820121 | 1100 | 0.285 | 0.011 | 0.56
5820237 | 지상 7층 | 지상 7층 | 5820121 | 1010 | 0.2625 | 0.0101 | 0.525
5820238 | 지상 7층 | 지상 7층 | 5820121 | 940 | 0.245 | 0.0094 | 0.48
5820239 | 지상 7층 | 지상 7층 | 5820121 | 915 | 0.23875 | 0.00915 | 0.4775
5820240 | 지상 7층 | 지상 7층 | 5820121 | 915 | 0.23875 | 0.00915 | 0.4775
5820241 | 지상 7층 | 지상 7층 | 5820121 | 300 | 0.085 | 0.003 | 0.16
5820242 | 지상 7층 | 지상 7층 | 5820121 | 600 | 0.16 | 0.006 | 0.3
5820243 | 지상 7층 | 지상 7층 | 5820121 | 1100 | 0.285 | 0.011 | 0.56
5820248 | 지상 7층 | 지상 7층 | 5820121 | 940 | 0.245 | 0.0094 | 0.48
5820249 | 지상 7층 | 지상 7층 | 5820121 | 940 | 0.245 | 0.0094 | 0.48
5820250 | 지상 7층 | 지상 7층 | 5820121 | 915 | 0.23875 | 0.00915 | 0.4775
5820251 | 지상 7층 | 지상 7층 | 5820121 | 915 | 0.23875 | 0.00915 | 0.4775
5820252 | 지상 7층 | 지상 7층 | 5820121 | 300 | 0.085 | 0.003 | 0.16
5820253 | 지상 7층 | 지상 7층 | 5820121 | 600 | 0.16 | 0.006 | 0.3
5820254 | 지상 7층 | 지상 7층 | 5820121 | 1100 | 0.285 | 0.011 | 0.56
5820259 | 지상 7층 | 지상 7층 | 5820121 | 940 | 0.245 | 0.0094 | 0.48
5820260 | 지상 7층 | 지상 7층 | 5820121 | 940 | 0.245 | 0.0094 | 0.48
5820261 | 지상 7층 | 지상 7층 | 5820121 | 915 | 0.23875 | 0.00915 | 0.4775
5820262 | 지상 7층 | 지상 7층 | 5820121 | 915 | 0.23875 | 0.00915 | 0.4775
5820263 | 지상 7층 | 지상 7층 | 5820121 | 300 | 0.085 | 0.003 | 0.16
5820264 | 지상 7층 | 지상 7층 | 5820121 | 600 | 0.16 | 0.006 | 0.3
5820265 | 지상 7층 | 지상 7층 | 5820121 | 1100 | 0.285 | 0.011 | 0.56
5820270 | 지상 7층 | 지상 7층 | 5820121 | 940 | 0.245 | 0.0094 | 0.48
5820271 | 지상 7층 | 지상 7층 | 5820121 | 940 | 0.245 | 0.0094 | 0.48
5820272 | 지상 7층 | 지상 7층 | 5820121 | 915 | 0.23875 | 0.00915 | 0.4775
5820273 | 지상 7층 | 지상 7층 | 5820121 | 915 | 0.23875 | 0.00915 | 0.4775
5820274 | 지상 7층 | 지상 7층 | 5820121 | 300 | 0.085 | 0.003 | 0.16
5820275 | 지상 7층 | 지상 7층 | 5820121 | 600 | 0.16 | 0.006 | 0.3
5820276 | 지상 7층 | 지상 7층 | 5820121 | 1100 | 0.285 | 0.011 | 0.56
5820281 | 지상 7층 | 지상 7층 | 5820121 | 940 | 0.245 | 0.0094 | 0.48
5820282 | 지상 7층 | 지상 7층 | 5820121 | 940 | 0.245 | 0.0094 | 0.48
5820283 | 지상 7층 | 지상 7층 | 5820121 | 915 | 0.23875 | 0.00915 | 0.4775
5820284 | 지상 7층 | 지상 7층 | 5820121 | 915 | 0.23875 | 0.00915 | 0.4775
5820285 | 지상 7층 | 지상 7층 | 5820121 | 300 | 0.085 | 0.003 | 0.16
5820286 | 지상 7층 | 지상 7층 | 5820121 | 600 | 0.16 | 0.006 | 0.3
5820287 | 지상 7층 | 지상 7층 | 5820121 | 1100 | 0.285 | 0.011 | 0.56
5820292 | 지상 7층 | 지상 7층 | 5820121 | 935 | 0.24375 | 0.00935 | 0.4775
5820293 | 지상 7층 | 지상 7층 | 5820121 | 1010 | 0.2625 | 0.0101 | 0.525
5820294 | 지상 7층 | 지상 7층 | 5820121 | 1010 | 0.2625 | 0.0101 | 0.525
5820295 | 지상 7층 | 지상 7층 | 5820121 | 1010 | 0.2625 | 0.0101 | 0.525
5820296 | 지상 7층 | 지상 7층 | 5820121 | 300 | 0.085 | 0.003 | 0.16
5820297 | 지상 7층 | 지상 7층 | 5820121 | 600 | 0.16 | 0.006 | 0.3
5820298 | 지상 7층 | 지상 7층 | 5820121 | 1100 | 0.285 | 0.011 | 0.56
5820303 | 지상 7층 | 지상 7층 | 5820121 | 1010 | 0.2625 | 0.0101 | 0.525
5820304 | 지상 7층 | 지상 7층 | 5820121 | 995 | 0.25875 | 0.00995 | 0.5075
5820305 | 지상 7층 | 지상 7층 | 5820121 | 970 | 0.2525 | 0.0097 | 0.505
5820306 | 지상 7층 | 지상 7층 | 5820121 | 970 | 0.2525 | 0.0097 | 0.505
5820307 | 지상 7층 | 지상 7층 | 5820121 | 300 | 0.085 | 0.003 | 0.16
5820308 | 지상 7층 | 지상 7층 | 5820121 | 600 | 0.16 | 0.006 | 0.3
5820309 | 지상 7층 | 지상 7층 | 5820121 | 1100 | 0.285 | 0.011 | 0.56
5820314 | 지상 7층 | 지상 7층 | 5820121 | 940 | 0.245 | 0.0094 | 0.48
5820315 | 지상 7층 | 지상 7층 | 5820121 | 940 | 0.245 | 0.0094 | 0.48
5820316 | 지상 7층 | 지상 7층 | 5820121 | 915 | 0.23875 | 0.00915 | 0.4775
5820317 | 지상 7층 | 지상 7층 | 5820121 | 915 | 0.23875 | 0.00915 | 0.4775
5820318 | 지상 7층 | 지상 7층 | 5820121 | 300 | 0.085 | 0.003 | 0.16
5820319 | 지상 7층 | 지상 7층 | 5820121 | 600 | 0.16 | 0.006 | 0.3
5820320 | 지상 7층 | 지상 7층 | 5820121 | 1100 | 0.285 | 0.011 | 0.56
5820325 | 지상 7층 | 지상 7층 | 5820121 | 940 | 0.245 | 0.0094 | 0.48
5820326 | 지상 7층 | 지상 7층 | 5820121 | 940 | 0.245 | 0.0094 | 0.48
5820327 | 지상 7층 | 지상 7층 | 5820121 | 915 | 0.23875 | 0.00915 | 0.4775
5820328 | 지상 7층 | 지상 7층 | 5820121 | 915 | 0.23875 | 0.00915 | 0.4775
5820329 | 지상 7층 | 지상 7층 | 5820121 | 300 | 0.085 | 0.003 | 0.16
5820330 | 지상 7층 | 지상 7층 | 5820121 | 600 | 0.16 | 0.006 | 0.3
5820331 | 지상 7층 | 지상 7층 | 5820121 | 1100 | 0.285 | 0.011 | 0.56
5820336 | 지상 7층 | 지상 7층 | 5820121 | 940 | 0.245 | 0.0094 | 0.48
5820337 | 지상 7층 | 지상 7층 | 5820121 | 940 | 0.245 | 0.0094 | 0.48
5820338 | 지상 7층 | 지상 7층 | 5820121 | 915 | 0.23875 | 0.00915 | 0.4775
5820339 | 지상 7층 | 지상 7층 | 5820121 | 915 | 0.23875 | 0.00915 | 0.4775
5820340 | 지상 7층 | 지상 7층 | 5820121 | 300 | 0.085 | 0.003 | 0.16
5820341 | 지상 7층 | 지상 7층 | 5820121 | 600 | 0.16 | 0.006 | 0.3
5820342 | 지상 7층 | 지상 7층 | 5820121 | 1100 | 0.285 | 0.011 | 0.56
5820347 | 지상 7층 | 지상 7층 | 5820121 | 940 | 0.245 | 0.0094 | 0.48
5820348 | 지상 7층 | 지상 7층 | 5820121 | 1015 | 0.26375 | 0.01015 | 0.5275
5820349 | 지상 7층 | 지상 7층 | 5820121 | 1015 | 0.26375 | 0.01015 | 0.5275
5820350 | 지상 7층 | 지상 7층 | 5820121 | 1015 | 0.26375 | 0.01015 | 0.5275
5820351 | 지상 7층 | 지상 7층 | 5820121 | 300 | 0.085 | 0.003 | 0.16
5820352 | 지상 7층 | 지상 7층 | 5820121 | 600 | 0.16 | 0.006 | 0.3
5820353 | 지상 7층 | 지상 7층 | 5820121 | 1100 | 0.285 | 0.011 | 0.56
5820358 | 지상 7층 | 지상 7층 | 5820121 | 1015 | 0.26375 | 0.01015 | 0.5275
5820359 | 지상 7층 | 지상 7층 | 5820121 | 892.184 | 0.233046 | 0.00892184 | 0.466092
5820360 | 지상 7층 | 지상 7층 | 5820121 | 892.184 | 0.233046 | 0.00892184 | 0.466092
5820361 | 지상 7층 | 지상 7층 | 5820121 | 892.184 | 0.233046 | 0.00892184 | 0.466092
5820362 | 지상 7층 | 지상 7층 | 5820121 | 300 | 0.085 | 0.003 | 0.16
5820363 | 지상 7층 | 지상 7층 | 5820121 | 600 | 0.16 | 0.006 | 0.3
5820364 | 지상 7층 | 지상 7층 | 5820121 | 1100 | 0.285 | 0.011 | 0.56
5820369 | 지상 7층 | 지상 7층 | 5820121 | 970 | 0.2525 | 0.0097 | 0.495
5820370 | 지상 7층 | 지상 7층 | 5820121 | 940 | 0.245 | 0.0094 | 0.48
5820371 | 지상 7층 | 지상 7층 | 5820121 | 915 | 0.23875 | 0.00915 | 0.4775
5820372 | 지상 7층 | 지상 7층 | 5820121 | 915 | 0.23875 | 0.00915 | 0.4775
5820373 | 지상 7층 | 지상 7층 | 5820121 | 650 | 0.1725 | 0.0065 | 0.345
5820378 | 지상 7층 | 지상 7층 | 5820121 | 940 | 0.245 | 0.0094 | 0.48
5820379 | 지상 7층 | 지상 7층 | 5820121 | 915 | 0.23875 | 0.00915 | 0.4775
5820380 | 지상 7층 | 지상 7층 | 5820121 | 915 | 0.23875 | 0.00915 | 0.4775
5820381 | 지상 7층 | 지상 7층 | 5820121 | 940 | 0.245 | 0.0094 | 0.48
5820382 | 지상 7층 | 지상 7층 | 5820121 | 650 | 0.1725 | 0.0065 | 0.345
5820387 | 지상 7층 | 지상 7층 | 5820121 | 940 | 0.245 | 0.0094 | 0.48
5820388 | 지상 7층 | 지상 7층 | 5820121 | 915 | 0.23875 | 0.00915 | 0.4775
5820389 | 지상 7층 | 지상 7층 | 5820121 | 915 | 0.23875 | 0.00915 | 0.4775
5820390 | 지상 7층 | 지상 7층 | 5820121 | 940 | 0.245 | 0.0094 | 0.48
5820391 | 지상 7층 | 지상 7층 | 5820121 | 650 | 0.1725 | 0.0065 | 0.345
5820396 | 지상 7층 | 지상 7층 | 5820121 | 940 | 0.245 | 0.0094 | 0.48
5820397 | 지상 7층 | 지상 7층 | 5820121 | 915 | 0.23875 | 0.00915 | 0.4775
5820398 | 지상 7층 | 지상 7층 | 5820121 | 915 | 0.23875 | 0.00915 | 0.4775
5820399 | 지상 7층 | 지상 7층 | 5820121 | 940 | 0.245 | 0.0094 | 0.48
5820400 | 지상 7층 | 지상 7층 | 5820121 | 650 | 0.1725 | 0.0065 | 0.345
5820405 | 지상 7층 | 지상 7층 | 5820121 | 940 | 0.245 | 0.0094 | 0.48
5820406 | 지상 7층 | 지상 7층 | 5820121 | 915 | 0.23875 | 0.00915 | 0.4775
5820407 | 지상 7층 | 지상 7층 | 5820121 | 915 | 0.23875 | 0.00915 | 0.4775
5820408 | 지상 7층 | 지상 7층 | 5820121 | 940 | 0.245 | 0.0094 | 0.48
5820409 | 지상 7층 | 지상 7층 | 5820121 | 650 | 0.1725 | 0.0065 | 0.345
5820414 | 지상 7층 | 지상 7층 | 5820121 | 970 | 0.2525 | 0.0097 | 0.495
5820415 | 지상 7층 | 지상 7층 | 5820121 | 945 | 0.24625 | 0.00945 | 0.4925
5820416 | 지상 7층 | 지상 7층 | 5820121 | 945 | 0.24625 | 0.00945 | 0.4925
5820417 | 지상 7층 | 지상 7층 | 5820121 | 940 | 0.245 | 0.0094 | 0.48
5820418 | 지상 7층 | 지상 7층 | 5820121 | 650 | 0.1725 | 0.0065 | 0.345
5820423 | 지상 7층 | 지상 7층 | 5820121 | 1110 | 0.2875 | 0.0111 | 0.565
5820424 | 지상 7층 | 지상 7층 | 5820121 | 1085.02 | 0.281254 | 0.0108502 | 0.562508
5820425 | 지상 7층 | 지상 7층 | 5820121 | 1085.02 | 0.281254 | 0.0108502 | 0.562508
5820426 | 지상 7층 | 지상 7층 | 5820121 | 1080 | 0.28 | 0.0108 | 0.55
5820427 | 지상 7층 | 지상 7층 | 5820121 | 650 | 0.1725 | 0.0065 | 0.345
5820432 | 지상 7층 | 지상 7층 | 5820121 | 940 | 0.245 | 0.0094 | 0.48
5820433 | 지상 7층 | 지상 7층 | 5820121 | 915 | 0.23875 | 0.00915 | 0.4775
5820434 | 지상 7층 | 지상 7층 | 5820121 | 915 | 0.23875 | 0.00915 | 0.4775
5820435 | 지상 7층 | 지상 7층 | 5820121 | 940 | 0.245 | 0.0094 | 0.48
5820436 | 지상 7층 | 지상 7층 | 5820121 | 650 | 0.1725 | 0.0065 | 0.345
5820441 | 지상 7층 | 지상 7층 | 5820121 | 940 | 0.245 | 0.0094 | 0.48
5820442 | 지상 7층 | 지상 7층 | 5820121 | 915 | 0.23875 | 0.00915 | 0.4775
5820443 | 지상 7층 | 지상 7층 | 5820121 | 915 | 0.23875 | 0.00915 | 0.4775
5820444 | 지상 7층 | 지상 7층 | 5820121 | 940 | 0.245 | 0.0094 | 0.48
5820445 | 지상 7층 | 지상 7층 | 5820121 | 650 | 0.1725 | 0.0065 | 0.345
5820450 | 지상 7층 | 지상 7층 | 5820121 | 940 | 0.245 | 0.0094 | 0.48
5820451 | 지상 7층 | 지상 7층 | 5820121 | 915 | 0.23875 | 0.00915 | 0.4775
5820452 | 지상 7층 | 지상 7층 | 5820121 | 915 | 0.23875 | 0.00915 | 0.4775
5820453 | 지상 7층 | 지상 7층 | 5820121 | 940 | 0.245 | 0.0094 | 0.48
5820454 | 지상 7층 | 지상 7층 | 5820121 | 650 | 0.1725 | 0.0065 | 0.345
5820459 | 지상 7층 | 지상 7층 | 5820121 | 940 | 0.245 | 0.0094 | 0.48
5820460 | 지상 7층 | 지상 7층 | 5820121 | 915 | 0.23875 | 0.00915 | 0.4775
5820461 | 지상 7층 | 지상 7층 | 5820121 | 915 | 0.23875 | 0.00915 | 0.4775
5820462 | 지상 7층 | 지상 7층 | 5820121 | 940 | 0.245 | 0.0094 | 0.48
5820463 | 지상 7층 | 지상 7층 | 5820121 | 650 | 0.1725 | 0.0065 | 0.345
5820468 | 지상 7층 | 지상 7층 | 5820121 | 935 | 0.24375 | 0.00935 | 0.4775
5820469 | 지상 7층 | 지상 7층 | 5820121 | 910 | 0.2375 | 0.0091 | 0.475
5820470 | 지상 7층 | 지상 7층 | 5820121 | 910 | 0.2375 | 0.0091 | 0.475
5820471 | 지상 7층 | 지상 7층 | 5820121 | 940 | 0.245 | 0.0094 | 0.48
5820472 | 지상 7층 | 지상 7층 | 5820121 | 650 | 0.1725 | 0.0065 | 0.345
5820477 | 지상 7층 | 지상 7층 | 5820121 | 940 | 0.245 | 0.0094 | 0.48
5820478 | 지상 7층 | 지상 7층 | 5820121 | 915 | 0.23875 | 0.00915 | 0.4775
5820479 | 지상 7층 | 지상 7층 | 5820121 | 915 | 0.23875 | 0.00915 | 0.4775
5820480 | 지상 7층 | 지상 7층 | 5820121 | 995 | 0.25875 | 0.00995 | 0.5075
5820481 | 지상 7층 | 지상 7층 | 5820121 | 650 | 0.1725 | 0.0065 | 0.345
5820486 | 지상 7층 | 지상 7층 | 5820121 | 940 | 0.245 | 0.0094 | 0.48
5820487 | 지상 7층 | 지상 7층 | 5820121 | 915 | 0.23875 | 0.00915 | 0.4775
5820488 | 지상 7층 | 지상 7층 | 5820121 | 915 | 0.23875 | 0.00915 | 0.4775
5820489 | 지상 7층 | 지상 7층 | 5820121 | 940 | 0.245 | 0.0094 | 0.48
5820490 | 지상 7층 | 지상 7층 | 5820121 | 650 | 0.1725 | 0.0065 | 0.345
5820495 | 지상 7층 | 지상 7층 | 5820121 | 940 | 0.245 | 0.0094 | 0.48
5820496 | 지상 7층 | 지상 7층 | 5820121 | 915 | 0.23875 | 0.00915 | 0.4775
5820497 | 지상 7층 | 지상 7층 | 5820121 | 915 | 0.23875 | 0.00915 | 0.4775
5820498 | 지상 7층 | 지상 7층 | 5820121 | 940 | 0.245 | 0.0094 | 0.48
5820499 | 지상 7층 | 지상 7층 | 5820121 | 650 | 0.1725 | 0.0065 | 0.345
5820504 | 지상 7층 | 지상 7층 | 5820121 | 940 | 0.245 | 0.0094 | 0.48
5820505 | 지상 7층 | 지상 7층 | 5820121 | 915 | 0.23875 | 0.00915 | 0.4775
5820506 | 지상 7층 | 지상 7층 | 5820121 | 915 | 0.23875 | 0.00915 | 0.4775
5820507 | 지상 7층 | 지상 7층 | 5820121 | 940 | 0.245 | 0.0094 | 0.48
5820508 | 지상 7층 | 지상 7층 | 5820121 | 650 | 0.1725 | 0.0065 | 0.345
5820511 | 지상 7층 | 지상 7층 | 5820509 | 912.5 | 0.238125 | 0.009125 | 0.47625
5820512 | 지상 7층 | 지상 7층 | 5820509 | 178.395 | 0.0545986 | 0.00178395 | 0.109197
5820514 | 지상 7층 | 지상 7층 | 5820509 | 1100 | 0.285 | 0.011 | 0.56
5820518 | 지상 7층 | 지상 7층 | 5820509 | 300 | 0.085 | 0.003 | 0.16
5820519 | 지상 7층 | 지상 7층 | 5820509 | 178.395 | 0.0545986 | 0.00178395 | 0.109197
5820523 | 지상 7층 | 지상 7층 | 5820509 | 600 | 0.16 | 0.006 | 0.3
5820524 | 지상 7층 | 지상 7층 | 5820509 | 178.395 | 0.0545986 | 0.00178395 | 0.109197
5820529 | 지상 7층 | 지상 7층 | 5820509 | 178.395 | 0.0545986 | 0.00178395 | 0.109197
5820530 | 지상 7층 | 지상 7층 | 5820509 | 828.5 | 0.217125 | 0.008285 | 0.42425
5820531 | 지상 7층 | 지상 7층 | 5820509 | 803.5 | 0.210875 | 0.008035 | 0.42175
5820532 | 지상 7층 | 지상 7층 | 5820509 | 803.5 | 0.210875 | 0.008035 | 0.42175
5820533 | 지상 7층 | 지상 7층 | 5820509 | 300 | 0.085 | 0.003 | 0.16
5820534 | 지상 7층 | 지상 7층 | 5820509 | 600 | 0.16 | 0.006 | 0.3
5820535 | 지상 7층 | 지상 7층 | 5820509 | 1100 | 0.285 | 0.011 | 0.56
5820540 | 지상 7층 | 지상 7층 | 5820509 | 828.5 | 0.217125 | 0.008285 | 0.42425
5820541 | 지상 7층 | 지상 7층 | 5820509 | 828.5 | 0.217125 | 0.008285 | 0.42425
5820542 | 지상 7층 | 지상 7층 | 5820509 | 803.5 | 0.210875 | 0.008035 | 0.42175
5820543 | 지상 7층 | 지상 7층 | 5820509 | 803.5 | 0.210875 | 0.008035 | 0.42175
5820544 | 지상 7층 | 지상 7층 | 5820509 | 300 | 0.085 | 0.003 | 0.16
5820545 | 지상 7층 | 지상 7층 | 5820509 | 600 | 0.16 | 0.006 | 0.3
5820546 | 지상 7층 | 지상 7층 | 5820509 | 1100 | 0.285 | 0.011 | 0.56
5820551 | 지상 7층 | 지상 7층 | 5820509 | 828.5 | 0.217125 | 0.008285 | 0.42425
5820552 | 지상 7층 | 지상 7층 | 5820509 | 828.5 | 0.217125 | 0.008285 | 0.42425
5820553 | 지상 7층 | 지상 7층 | 5820509 | 803.5 | 0.210875 | 0.008035 | 0.42175
5820554 | 지상 7층 | 지상 7층 | 5820509 | 803.5 | 0.210875 | 0.008035 | 0.42175
5820555 | 지상 7층 | 지상 7층 | 5820509 | 300 | 0.085 | 0.003 | 0.16
5820556 | 지상 7층 | 지상 7층 | 5820509 | 600 | 0.16 | 0.006 | 0.3
5820557 | 지상 7층 | 지상 7층 | 5820509 | 1100 | 0.285 | 0.011 | 0.56
5820562 | 지상 7층 | 지상 7층 | 5820509 | 828.5 | 0.217125 | 0.008285 | 0.42425
5820563 | 지상 7층 | 지상 7층 | 5820509 | 828.5 | 0.217125 | 0.008285 | 0.42425
5820564 | 지상 7층 | 지상 7층 | 5820509 | 803.5 | 0.210875 | 0.008035 | 0.42175
5820565 | 지상 7층 | 지상 7층 | 5820509 | 803.5 | 0.210875 | 0.008035 | 0.42175
5820566 | 지상 7층 | 지상 7층 | 5820509 | 300 | 0.085 | 0.003 | 0.16
5820567 | 지상 7층 | 지상 7층 | 5820509 | 600 | 0.16 | 0.006 | 0.3
5820568 | 지상 7층 | 지상 7층 | 5820509 | 1100 | 0.285 | 0.011 | 0.56
5820573 | 지상 7층 | 지상 7층 | 5820509 | 828.5 | 0.217125 | 0.008285 | 0.42425
5820574 | 지상 7층 | 지상 7층 | 5820509 | 1120 | 0.29 | 0.0112 | 0.58
5820575 | 지상 7층 | 지상 7층 | 5820509 | 1120 | 0.29 | 0.0112 | 0.58
5820576 | 지상 7층 | 지상 7층 | 5820509 | 1120 | 0.29 | 0.0112 | 0.58
5820577 | 지상 7층 | 지상 7층 | 5820509 | 300 | 0.085 | 0.003 | 0.16
5820578 | 지상 7층 | 지상 7층 | 5820509 | 600 | 0.16 | 0.006 | 0.3
5820579 | 지상 7층 | 지상 7층 | 5820509 | 1100 | 0.285 | 0.011 | 0.56
5820584 | 지상 7층 | 지상 7층 | 5820509 | 1120 | 0.29 | 0.0112 | 0.58
5820585 | 지상 7층 | 지상 7층 | 5820509 | 754 | 0.1985 | 0.00754 | 0.387
5820586 | 지상 7층 | 지상 7층 | 5820509 | 729 | 0.19225 | 0.00729 | 0.3845
5820587 | 지상 7층 | 지상 7층 | 5820509 | 729 | 0.19225 | 0.00729 | 0.3845
5820588 | 지상 7층 | 지상 7층 | 5820509 | 300 | 0.085 | 0.003 | 0.16
5820589 | 지상 7층 | 지상 7층 | 5820509 | 600 | 0.16 | 0.006 | 0.3
5820590 | 지상 7층 | 지상 7층 | 5820509 | 1100 | 0.285 | 0.011 | 0.56
5820595 | 지상 7층 | 지상 7층 | 5820509 | 754 | 0.1985 | 0.00754 | 0.387
5820596 | 지상 7층 | 지상 7층 | 5820509 | 754 | 0.1985 | 0.00754 | 0.387
5820597 | 지상 7층 | 지상 7층 | 5820509 | 729 | 0.19225 | 0.00729 | 0.3845
5820598 | 지상 7층 | 지상 7층 | 5820509 | 729 | 0.19225 | 0.00729 | 0.3845
5820599 | 지상 7층 | 지상 7층 | 5820509 | 300 | 0.085 | 0.003 | 0.16
5820600 | 지상 7층 | 지상 7층 | 5820509 | 600 | 0.16 | 0.006 | 0.3
5820601 | 지상 7층 | 지상 7층 | 5820509 | 1100 | 0.285 | 0.011 | 0.56
5820606 | 지상 7층 | 지상 7층 | 5820509 | 754 | 0.1985 | 0.00754 | 0.387
5820607 | 지상 7층 | 지상 7층 | 5820509 | 754 | 0.1985 | 0.00754 | 0.387
5820608 | 지상 7층 | 지상 7층 | 5820509 | 729 | 0.19225 | 0.00729 | 0.3845
5820609 | 지상 7층 | 지상 7층 | 5820509 | 729 | 0.19225 | 0.00729 | 0.3845
5820610 | 지상 7층 | 지상 7층 | 5820509 | 300 | 0.085 | 0.003 | 0.16
5820611 | 지상 7층 | 지상 7층 | 5820509 | 600 | 0.16 | 0.006 | 0.3
5820612 | 지상 7층 | 지상 7층 | 5820509 | 1100 | 0.285 | 0.011 | 0.56
5820617 | 지상 7층 | 지상 7층 | 5820509 | 754 | 0.1985 | 0.00754 | 0.387
5820618 | 지상 7층 | 지상 7층 | 5820509 | 754 | 0.1985 | 0.00754 | 0.387
5820619 | 지상 7층 | 지상 7층 | 5820509 | 729 | 0.19225 | 0.00729 | 0.3845
5820620 | 지상 7층 | 지상 7층 | 5820509 | 729 | 0.19225 | 0.00729 | 0.3845
5820621 | 지상 7층 | 지상 7층 | 5820509 | 300 | 0.085 | 0.003 | 0.16
5820622 | 지상 7층 | 지상 7층 | 5820509 | 600 | 0.16 | 0.006 | 0.3
5820623 | 지상 7층 | 지상 7층 | 5820509 | 1100 | 0.285 | 0.011 | 0.56
5820628 | 지상 7층 | 지상 7층 | 5820509 | 754 | 0.1985 | 0.00754 | 0.387
5820629 | 지상 7층 | 지상 7층 | 5820509 | 1120 | 0.29 | 0.0112 | 0.58
5820630 | 지상 7층 | 지상 7층 | 5820509 | 1120 | 0.29 | 0.0112 | 0.58
5820631 | 지상 7층 | 지상 7층 | 5820509 | 1120 | 0.29 | 0.0112 | 0.58
5820632 | 지상 7층 | 지상 7층 | 5820509 | 300 | 0.085 | 0.003 | 0.16
5820633 | 지상 7층 | 지상 7층 | 5820509 | 600 | 0.16 | 0.006 | 0.3
5820634 | 지상 7층 | 지상 7층 | 5820509 | 1100 | 0.285 | 0.011 | 0.56
5820639 | 지상 7층 | 지상 7층 | 5820509 | 1120 | 0.29 | 0.0112 | 0.58
5820640 | 지상 7층 | 지상 7층 | 5820509 | 741.5 | 0.195375 | 0.007415 | 0.38075
5820641 | 지상 7층 | 지상 7층 | 5820509 | 716.5 | 0.189125 | 0.007165 | 0.37825
5820642 | 지상 7층 | 지상 7층 | 5820509 | 716.5 | 0.189125 | 0.007165 | 0.37825
5820643 | 지상 7층 | 지상 7층 | 5820509 | 300 | 0.085 | 0.003 | 0.16
5820644 | 지상 7층 | 지상 7층 | 5820509 | 600 | 0.16 | 0.006 | 0.3
5820645 | 지상 7층 | 지상 7층 | 5820509 | 1100 | 0.285 | 0.011 | 0.56
5820650 | 지상 7층 | 지상 7층 | 5820509 | 741.5 | 0.195375 | 0.007415 | 0.38075
5820651 | 지상 7층 | 지상 7층 | 5820509 | 741.5 | 0.195375 | 0.007415 | 0.38075
5820652 | 지상 7층 | 지상 7층 | 5820509 | 716.5 | 0.189125 | 0.007165 | 0.37825
5820653 | 지상 7층 | 지상 7층 | 5820509 | 716.5 | 0.189125 | 0.007165 | 0.37825
5820654 | 지상 7층 | 지상 7층 | 5820509 | 300 | 0.085 | 0.003 | 0.16
5820655 | 지상 7층 | 지상 7층 | 5820509 | 600 | 0.16 | 0.006 | 0.3
5820656 | 지상 7층 | 지상 7층 | 5820509 | 1100 | 0.285 | 0.011 | 0.56
5820661 | 지상 7층 | 지상 7층 | 5820509 | 741.5 | 0.195375 | 0.007415 | 0.38075
5820662 | 지상 7층 | 지상 7층 | 5820509 | 741.5 | 0.195375 | 0.007415 | 0.38075
5820663 | 지상 7층 | 지상 7층 | 5820509 | 716.5 | 0.189125 | 0.007165 | 0.37825
5820664 | 지상 7층 | 지상 7층 | 5820509 | 716.5 | 0.189125 | 0.007165 | 0.37825
5820665 | 지상 7층 | 지상 7층 | 5820509 | 300 | 0.085 | 0.003 | 0.16
5820666 | 지상 7층 | 지상 7층 | 5820509 | 600 | 0.16 | 0.006 | 0.3
5820667 | 지상 7층 | 지상 7층 | 5820509 | 1100 | 0.285 | 0.011 | 0.56
5820672 | 지상 7층 | 지상 7층 | 5820509 | 741.5 | 0.195375 | 0.007415 | 0.38075
5820673 | 지상 7층 | 지상 7층 | 5820509 | 741.5 | 0.195375 | 0.007415 | 0.38075
5820674 | 지상 7층 | 지상 7층 | 5820509 | 716.5 | 0.189125 | 0.007165 | 0.37825
5820675 | 지상 7층 | 지상 7층 | 5820509 | 716.5 | 0.189125 | 0.007165 | 0.37825
5820676 | 지상 7층 | 지상 7층 | 5820509 | 300 | 0.085 | 0.003 | 0.16
5820677 | 지상 7층 | 지상 7층 | 5820509 | 600 | 0.16 | 0.006 | 0.3
5820678 | 지상 7층 | 지상 7층 | 5820509 | 1100 | 0.285 | 0.011 | 0.56
5820683 | 지상 7층 | 지상 7층 | 5820509 | 741.5 | 0.195375 | 0.007415 | 0.38075
5820684 | 지상 7층 | 지상 7층 | 5820509 | 1120 | 0.29 | 0.0112 | 0.58
5820685 | 지상 7층 | 지상 7층 | 5820509 | 1120 | 0.29 | 0.0112 | 0.58
5820686 | 지상 7층 | 지상 7층 | 5820509 | 1120 | 0.29 | 0.0112 | 0.58
5820687 | 지상 7층 | 지상 7층 | 5820509 | 300 | 0.085 | 0.003 | 0.16
5820688 | 지상 7층 | 지상 7층 | 5820509 | 600 | 0.16 | 0.006 | 0.3
5820689 | 지상 7층 | 지상 7층 | 5820509 | 1100 | 0.285 | 0.011 | 0.56
5820694 | 지상 7층 | 지상 7층 | 5820509 | 1120 | 0.29 | 0.0112 | 0.58
5820695 | 지상 7층 | 지상 7층 | 5820509 | 743.357 | 0.195839 | 0.00743357 | 0.381679
5820696 | 지상 7층 | 지상 7층 | 5820509 | 718.357 | 0.189589 | 0.00718357 | 0.379179
5820697 | 지상 7층 | 지상 7층 | 5820509 | 718.357 | 0.189589 | 0.00718357 | 0.379179
5820698 | 지상 7층 | 지상 7층 | 5820509 | 300 | 0.085 | 0.003 | 0.16
5820699 | 지상 7층 | 지상 7층 | 5820509 | 600 | 0.16 | 0.006 | 0.3
5820700 | 지상 7층 | 지상 7층 | 5820509 | 1100 | 0.285 | 0.011 | 0.56
5820705 | 지상 7층 | 지상 7층 | 5820509 | 743.357 | 0.195839 | 0.00743357 | 0.381679
5820706 | 지상 7층 | 지상 7층 | 5820509 | 743.357 | 0.195839 | 0.00743357 | 0.381679
5820707 | 지상 7층 | 지상 7층 | 5820509 | 718.357 | 0.189589 | 0.00718357 | 0.379179
5820708 | 지상 7층 | 지상 7층 | 5820509 | 718.357 | 0.189589 | 0.00718357 | 0.379179
5820709 | 지상 7층 | 지상 7층 | 5820509 | 300 | 0.085 | 0.003 | 0.16
5820710 | 지상 7층 | 지상 7층 | 5820509 | 600 | 0.16 | 0.006 | 0.3
5820711 | 지상 7층 | 지상 7층 | 5820509 | 1100 | 0.285 | 0.011 | 0.56
5820716 | 지상 7층 | 지상 7층 | 5820509 | 743.357 | 0.195839 | 0.00743357 | 0.381679
5820717 | 지상 7층 | 지상 7층 | 5820509 | 743.357 | 0.195839 | 0.00743357 | 0.381679
5820718 | 지상 7층 | 지상 7층 | 5820509 | 718.357 | 0.189589 | 0.00718357 | 0.379179
5820719 | 지상 7층 | 지상 7층 | 5820509 | 718.357 | 0.189589 | 0.00718357 | 0.379179
5820720 | 지상 7층 | 지상 7층 | 5820509 | 300 | 0.085 | 0.003 | 0.16
5820721 | 지상 7층 | 지상 7층 | 5820509 | 600 | 0.16 | 0.006 | 0.3
5820722 | 지상 7층 | 지상 7층 | 5820509 | 1100 | 0.285 | 0.011 | 0.56
5820727 | 지상 7층 | 지상 7층 | 5820509 | 743.357 | 0.195839 | 0.00743357 | 0.381679
5820728 | 지상 7층 | 지상 7층 | 5820509 | 743.357 | 0.195839 | 0.00743357 | 0.381679
5820729 | 지상 7층 | 지상 7층 | 5820509 | 718.357 | 0.189589 | 0.00718357 | 0.379179
5820730 | 지상 7층 | 지상 7층 | 5820509 | 718.357 | 0.189589 | 0.00718357 | 0.379179
5820731 | 지상 7층 | 지상 7층 | 5820509 | 300 | 0.085 | 0.003 | 0.16
5820732 | 지상 7층 | 지상 7층 | 5820509 | 600 | 0.16 | 0.006 | 0.3
5820733 | 지상 7층 | 지상 7층 | 5820509 | 1100 | 0.285 | 0.011 | 0.56
5820738 | 지상 7층 | 지상 7층 | 5820509 | 743.357 | 0.195839 | 0.00743357 | 0.381679
5820739 | 지상 7층 | 지상 7층 | 5820509 | 743.357 | 0.195839 | 0.00743357 | 0.381679
5820740 | 지상 7층 | 지상 7층 | 5820509 | 718.357 | 0.189589 | 0.00718357 | 0.379179
5820741 | 지상 7층 | 지상 7층 | 5820509 | 718.357 | 0.189589 | 0.00718357 | 0.379179
5820742 | 지상 7층 | 지상 7층 | 5820509 | 300 | 0.085 | 0.003 | 0.16
5820743 | 지상 7층 | 지상 7층 | 5820509 | 600 | 0.16 | 0.006 | 0.3
5820744 | 지상 7층 | 지상 7층 | 5820509 | 1100 | 0.285 | 0.011 | 0.56
5820749 | 지상 7층 | 지상 7층 | 5820509 | 743.357 | 0.195839 | 0.00743357 | 0.381679
5820750 | 지상 7층 | 지상 7층 | 5820509 | 743.357 | 0.195839 | 0.00743357 | 0.381679
5820751 | 지상 7층 | 지상 7층 | 5820509 | 718.357 | 0.189589 | 0.00718357 | 0.379179
5820752 | 지상 7층 | 지상 7층 | 5820509 | 718.357 | 0.189589 | 0.00718357 | 0.379179
5820753 | 지상 7층 | 지상 7층 | 5820509 | 300 | 0.085 | 0.003 | 0.16
5820754 | 지상 7층 | 지상 7층 | 5820509 | 600 | 0.16 | 0.006 | 0.3
5820755 | 지상 7층 | 지상 7층 | 5820509 | 1100 | 0.285 | 0.011 | 0.56
5820760 | 지상 7층 | 지상 7층 | 5820509 | 743.357 | 0.195839 | 0.00743357 | 0.381679
5820761 | 지상 7층 | 지상 7층 | 5820509 | 743.357 | 0.195839 | 0.00743357 | 0.381679
5820762 | 지상 7층 | 지상 7층 | 5820509 | 718.357 | 0.189589 | 0.00718357 | 0.379179
5820763 | 지상 7층 | 지상 7층 | 5820509 | 718.357 | 0.189589 | 0.00718357 | 0.379179
5820764 | 지상 7층 | 지상 7층 | 5820509 | 300 | 0.085 | 0.003 | 0.16
5820765 | 지상 7층 | 지상 7층 | 5820509 | 600 | 0.16 | 0.006 | 0.3
5820766 | 지상 7층 | 지상 7층 | 5820509 | 1100 | 0.285 | 0.011 | 0.56
5820771 | 지상 7층 | 지상 7층 | 5820509 | 743.357 | 0.195839 | 0.00743357 | 0.381679
5820772 | 지상 7층 | 지상 7층 | 5820509 | 912.5 | 0.238125 | 0.009125 | 0.47625
5820773 | 지상 7층 | 지상 7층 | 5820509 | 912.5 | 0.238125 | 0.009125 | 0.47625
5820774 | 지상 7층 | 지상 7층 | 5820509 | 912.5 | 0.238125 | 0.009125 | 0.47625
5820775 | 지상 7층 | 지상 7층 | 5820509 | 300 | 0.085 | 0.003 | 0.16
5820776 | 지상 7층 | 지상 7층 | 5820509 | 600 | 0.16 | 0.006 | 0.3
5820777 | 지상 7층 | 지상 7층 | 5820509 | 1100 | 0.285 | 0.011 | 0.56
5820782 | 지상 7층 | 지상 7층 | 5820509 | 828.5 | 0.217125 | 0.008285 | 0.42425
5820783 | 지상 7층 | 지상 7층 | 5820509 | 828.5 | 0.217125 | 0.008285 | 0.42425
5820784 | 지상 7층 | 지상 7층 | 5820509 | 803.5 | 0.210875 | 0.008035 | 0.42175
5820785 | 지상 7층 | 지상 7층 | 5820509 | 803.5 | 0.210875 | 0.008035 | 0.42175
5820786 | 지상 7층 | 지상 7층 | 5820509 | 650 | 0.1725 | 0.0065 | 0.345
5820791 | 지상 7층 | 지상 7층 | 5820509 | 828.5 | 0.217125 | 0.008285 | 0.42425
5820792 | 지상 7층 | 지상 7층 | 5820509 | 828.5 | 0.217125 | 0.008285 | 0.42425
5820793 | 지상 7층 | 지상 7층 | 5820509 | 803.5 | 0.210875 | 0.008035 | 0.42175
5820794 | 지상 7층 | 지상 7층 | 5820509 | 803.5 | 0.210875 | 0.008035 | 0.42175
5820795 | 지상 7층 | 지상 7층 | 5820509 | 650 | 0.1725 | 0.0065 | 0.345
5820800 | 지상 7층 | 지상 7층 | 5820509 | 828.5 | 0.217125 | 0.008285 | 0.42425
5820801 | 지상 7층 | 지상 7층 | 5820509 | 828.5 | 0.217125 | 0.008285 | 0.42425
5820802 | 지상 7층 | 지상 7층 | 5820509 | 803.5 | 0.210875 | 0.008035 | 0.42175
5820803 | 지상 7층 | 지상 7층 | 5820509 | 803.5 | 0.210875 | 0.008035 | 0.42175
5820804 | 지상 7층 | 지상 7층 | 5820509 | 650 | 0.1725 | 0.0065 | 0.345
5820809 | 지상 7층 | 지상 7층 | 5820509 | 828.5 | 0.217125 | 0.008285 | 0.42425
5820810 | 지상 7층 | 지상 7층 | 5820509 | 828.5 | 0.217125 | 0.008285 | 0.42425
5820811 | 지상 7층 | 지상 7층 | 5820509 | 803.5 | 0.210875 | 0.008035 | 0.42175
5820812 | 지상 7층 | 지상 7층 | 5820509 | 803.5 | 0.210875 | 0.008035 | 0.42175
5820813 | 지상 7층 | 지상 7층 | 5820509 | 650 | 0.1725 | 0.0065 | 0.345
5820818 | 지상 7층 | 지상 7층 | 5820509 | 754 | 0.1985 | 0.00754 | 0.387
5820819 | 지상 7층 | 지상 7층 | 5820509 | 754 | 0.1985 | 0.00754 | 0.387
5820820 | 지상 7층 | 지상 7층 | 5820509 | 729 | 0.19225 | 0.00729 | 0.3845
5820821 | 지상 7층 | 지상 7층 | 5820509 | 729 | 0.19225 | 0.00729 | 0.3845
5820822 | 지상 7층 | 지상 7층 | 5820509 | 650 | 0.1725 | 0.0065 | 0.345
5820827 | 지상 7층 | 지상 7층 | 5820509 | 754 | 0.1985 | 0.00754 | 0.387
5820828 | 지상 7층 | 지상 7층 | 5820509 | 754 | 0.1985 | 0.00754 | 0.387
5820829 | 지상 7층 | 지상 7층 | 5820509 | 729 | 0.19225 | 0.00729 | 0.3845
5820830 | 지상 7층 | 지상 7층 | 5820509 | 729 | 0.19225 | 0.00729 | 0.3845
5820831 | 지상 7층 | 지상 7층 | 5820509 | 650 | 0.1725 | 0.0065 | 0.345
5820836 | 지상 7층 | 지상 7층 | 5820509 | 754 | 0.1985 | 0.00754 | 0.387
5820837 | 지상 7층 | 지상 7층 | 5820509 | 754 | 0.1985 | 0.00754 | 0.387
5820838 | 지상 7층 | 지상 7층 | 5820509 | 729 | 0.19225 | 0.00729 | 0.3845
5820839 | 지상 7층 | 지상 7층 | 5820509 | 729 | 0.19225 | 0.00729 | 0.3845
5820840 | 지상 7층 | 지상 7층 | 5820509 | 650 | 0.1725 | 0.0065 | 0.345
5820845 | 지상 7층 | 지상 7층 | 5820509 | 754 | 0.1985 | 0.00754 | 0.387
5820846 | 지상 7층 | 지상 7층 | 5820509 | 754 | 0.1985 | 0.00754 | 0.387
5820847 | 지상 7층 | 지상 7층 | 5820509 | 729 | 0.19225 | 0.00729 | 0.3845
5820848 | 지상 7층 | 지상 7층 | 5820509 | 729 | 0.19225 | 0.00729 | 0.3845
5820849 | 지상 7층 | 지상 7층 | 5820509 | 650 | 0.1725 | 0.0065 | 0.345
5820854 | 지상 7층 | 지상 7층 | 5820509 | 741.5 | 0.195375 | 0.007415 | 0.38075
5820855 | 지상 7층 | 지상 7층 | 5820509 | 741.5 | 0.195375 | 0.007415 | 0.38075
5820856 | 지상 7층 | 지상 7층 | 5820509 | 716.5 | 0.189125 | 0.007165 | 0.37825
5820857 | 지상 7층 | 지상 7층 | 5820509 | 716.5 | 0.189125 | 0.007165 | 0.37825
5820858 | 지상 7층 | 지상 7층 | 5820509 | 650 | 0.1725 | 0.0065 | 0.345
5820863 | 지상 7층 | 지상 7층 | 5820509 | 741.5 | 0.195375 | 0.007415 | 0.38075
5820864 | 지상 7층 | 지상 7층 | 5820509 | 741.5 | 0.195375 | 0.007415 | 0.38075
5820865 | 지상 7층 | 지상 7층 | 5820509 | 716.5 | 0.189125 | 0.007165 | 0.37825
5820866 | 지상 7층 | 지상 7층 | 5820509 | 716.5 | 0.189125 | 0.007165 | 0.37825
5820867 | 지상 7층 | 지상 7층 | 5820509 | 650 | 0.1725 | 0.0065 | 0.345
5820872 | 지상 7층 | 지상 7층 | 5820509 | 741.5 | 0.195375 | 0.007415 | 0.38075
5820873 | 지상 7층 | 지상 7층 | 5820509 | 741.5 | 0.195375 | 0.007415 | 0.38075
5820874 | 지상 7층 | 지상 7층 | 5820509 | 716.5 | 0.189125 | 0.007165 | 0.37825
5820875 | 지상 7층 | 지상 7층 | 5820509 | 716.5 | 0.189125 | 0.007165 | 0.37825
5820876 | 지상 7층 | 지상 7층 | 5820509 | 650 | 0.1725 | 0.0065 | 0.345
5820881 | 지상 7층 | 지상 7층 | 5820509 | 741.5 | 0.195375 | 0.007415 | 0.38075
5820882 | 지상 7층 | 지상 7층 | 5820509 | 741.5 | 0.195375 | 0.007415 | 0.38075
5820883 | 지상 7층 | 지상 7층 | 5820509 | 716.5 | 0.189125 | 0.007165 | 0.37825
5820884 | 지상 7층 | 지상 7층 | 5820509 | 716.5 | 0.189125 | 0.007165 | 0.37825
5820885 | 지상 7층 | 지상 7층 | 5820509 | 650 | 0.1725 | 0.0065 | 0.345
5820890 | 지상 7층 | 지상 7층 | 5820509 | 743.357 | 0.195839 | 0.00743357 | 0.381679
5820891 | 지상 7층 | 지상 7층 | 5820509 | 743.357 | 0.195839 | 0.00743357 | 0.381679
5820892 | 지상 7층 | 지상 7층 | 5820509 | 718.357 | 0.189589 | 0.00718357 | 0.379179
5820893 | 지상 7층 | 지상 7층 | 5820509 | 718.357 | 0.189589 | 0.00718357 | 0.379179
5820894 | 지상 7층 | 지상 7층 | 5820509 | 650 | 0.1725 | 0.0065 | 0.345
5820899 | 지상 7층 | 지상 7층 | 5820509 | 743.357 | 0.195839 | 0.00743357 | 0.381679
5820900 | 지상 7층 | 지상 7층 | 5820509 | 743.357 | 0.195839 | 0.00743357 | 0.381679
5820901 | 지상 7층 | 지상 7층 | 5820509 | 718.357 | 0.189589 | 0.00718357 | 0.379179
5820902 | 지상 7층 | 지상 7층 | 5820509 | 718.357 | 0.189589 | 0.00718357 | 0.379179
5820903 | 지상 7층 | 지상 7층 | 5820509 | 650 | 0.1725 | 0.0065 | 0.345
5820908 | 지상 7층 | 지상 7층 | 5820509 | 743.357 | 0.195839 | 0.00743357 | 0.381679
5820909 | 지상 7층 | 지상 7층 | 5820509 | 743.357 | 0.195839 | 0.00743357 | 0.381679
5820910 | 지상 7층 | 지상 7층 | 5820509 | 718.357 | 0.189589 | 0.00718357 | 0.379179
5820911 | 지상 7층 | 지상 7층 | 5820509 | 718.357 | 0.189589 | 0.00718357 | 0.379179
5820912 | 지상 7층 | 지상 7층 | 5820509 | 650 | 0.1725 | 0.0065 | 0.345
5820917 | 지상 7층 | 지상 7층 | 5820509 | 743.357 | 0.195839 | 0.00743357 | 0.381679
5820918 | 지상 7층 | 지상 7층 | 5820509 | 743.357 | 0.195839 | 0.00743357 | 0.381679
5820919 | 지상 7층 | 지상 7층 | 5820509 | 718.357 | 0.189589 | 0.00718357 | 0.379179
5820920 | 지상 7층 | 지상 7층 | 5820509 | 718.357 | 0.189589 | 0.00718357 | 0.379179
5820921 | 지상 7층 | 지상 7층 | 5820509 | 650 | 0.1725 | 0.0065 | 0.345
5820926 | 지상 7층 | 지상 7층 | 5820509 | 743.357 | 0.195839 | 0.00743357 | 0.381679
5820927 | 지상 7층 | 지상 7층 | 5820509 | 743.357 | 0.195839 | 0.00743357 | 0.381679
5820928 | 지상 7층 | 지상 7층 | 5820509 | 718.357 | 0.189589 | 0.00718357 | 0.379179
5820929 | 지상 7층 | 지상 7층 | 5820509 | 718.357 | 0.189589 | 0.00718357 | 0.379179
5820930 | 지상 7층 | 지상 7층 | 5820509 | 650 | 0.1725 | 0.0065 | 0.345
5820935 | 지상 7층 | 지상 7층 | 5820509 | 743.357 | 0.195839 | 0.00743357 | 0.381679
5820936 | 지상 7층 | 지상 7층 | 5820509 | 743.357 | 0.195839 | 0.00743357 | 0.381679
5820937 | 지상 7층 | 지상 7층 | 5820509 | 718.357 | 0.189589 | 0.00718357 | 0.379179
5820938 | 지상 7층 | 지상 7층 | 5820509 | 718.357 | 0.189589 | 0.00718357 | 0.379179
5820939 | 지상 7층 | 지상 7층 | 5820509 | 650 | 0.1725 | 0.0065 | 0.345
5820944 | 지상 7층 | 지상 7층 | 5820509 | 743.357 | 0.195839 | 0.00743357 | 0.381679
5820945 | 지상 7층 | 지상 7층 | 5820509 | 743.357 | 0.195839 | 0.00743357 | 0.381679
5820946 | 지상 7층 | 지상 7층 | 5820509 | 718.357 | 0.189589 | 0.00718357 | 0.379179
5820947 | 지상 7층 | 지상 7층 | 5820509 | 718.357 | 0.189589 | 0.00718357 | 0.379179
5820948 | 지상 7층 | 지상 7층 | 5820509 | 650 | 0.1725 | 0.0065 | 0.345
5821011 | 지상 6층 | 지상 6층 | 5821009 | 892.184 | 0.233046 | 0.00892184 | 0.466092
5821012 | 지상 6층 | 지상 6층 | 5821009 | 912.816 | 0.238204 | 0.00912816 | 0.476408
5821017 | 지상 6층 | 지상 6층 | 5821009 | 912.816 | 0.238204 | 0.00912816 | 0.476408
5821021 | 지상 6층 | 지상 6층 | 5821009 | 912.816 | 0.238204 | 0.00912816 | 0.476408
5821026 | 지상 6층 | 지상 6층 | 5821009 | 912.816 | 0.238204 | 0.00912816 | 0.476408
5821027 | 지상 6층 | 지상 6층 | 5821009 | 970 | 0.2525 | 0.0097 | 0.495
5821028 | 지상 6층 | 지상 6층 | 5821009 | 945 | 0.24625 | 0.00945 | 0.4925
5821029 | 지상 6층 | 지상 6층 | 5821009 | 945 | 0.24625 | 0.00945 | 0.4925
5821030 | 지상 6층 | 지상 6층 | 5821009 | 300 | 0.085 | 0.003 | 0.16
5821031 | 지상 6층 | 지상 6층 | 5821009 | 600 | 0.16 | 0.006 | 0.3
5821032 | 지상 6층 | 지상 6층 | 5821009 | 1100 | 0.285 | 0.011 | 0.56
5821037 | 지상 6층 | 지상 6층 | 5821009 | 940 | 0.245 | 0.0094 | 0.48
5821038 | 지상 6층 | 지상 6층 | 5821009 | 940 | 0.245 | 0.0094 | 0.48
5821039 | 지상 6층 | 지상 6층 | 5821009 | 915 | 0.23875 | 0.00915 | 0.4775
5821040 | 지상 6층 | 지상 6층 | 5821009 | 915 | 0.23875 | 0.00915 | 0.4775
5821041 | 지상 6층 | 지상 6층 | 5821009 | 300 | 0.085 | 0.003 | 0.16
5821042 | 지상 6층 | 지상 6층 | 5821009 | 600 | 0.16 | 0.006 | 0.3
5821043 | 지상 6층 | 지상 6층 | 5821009 | 1100 | 0.285 | 0.011 | 0.56
5821048 | 지상 6층 | 지상 6층 | 5821009 | 940 | 0.245 | 0.0094 | 0.48
5821049 | 지상 6층 | 지상 6층 | 5821009 | 940 | 0.245 | 0.0094 | 0.48
5821050 | 지상 6층 | 지상 6층 | 5821009 | 915 | 0.23875 | 0.00915 | 0.4775
5821051 | 지상 6층 | 지상 6층 | 5821009 | 915 | 0.23875 | 0.00915 | 0.4775
5821052 | 지상 6층 | 지상 6층 | 5821009 | 300 | 0.085 | 0.003 | 0.16
5821053 | 지상 6층 | 지상 6층 | 5821009 | 600 | 0.16 | 0.006 | 0.3
5821054 | 지상 6층 | 지상 6층 | 5821009 | 1100 | 0.285 | 0.011 | 0.56
5821059 | 지상 6층 | 지상 6층 | 5821009 | 940 | 0.245 | 0.0094 | 0.48
5821060 | 지상 6층 | 지상 6층 | 5821009 | 940 | 0.245 | 0.0094 | 0.48
5821061 | 지상 6층 | 지상 6층 | 5821009 | 915 | 0.23875 | 0.00915 | 0.4775
5821062 | 지상 6층 | 지상 6층 | 5821009 | 915 | 0.23875 | 0.00915 | 0.4775
5821063 | 지상 6층 | 지상 6층 | 5821009 | 300 | 0.085 | 0.003 | 0.16
5821064 | 지상 6층 | 지상 6층 | 5821009 | 600 | 0.16 | 0.006 | 0.3
5821065 | 지상 6층 | 지상 6층 | 5821009 | 1100 | 0.285 | 0.011 | 0.56
5821070 | 지상 6층 | 지상 6층 | 5821009 | 940 | 0.245 | 0.0094 | 0.48
5821071 | 지상 6층 | 지상 6층 | 5821009 | 940 | 0.245 | 0.0094 | 0.48
5821072 | 지상 6층 | 지상 6층 | 5821009 | 915 | 0.23875 | 0.00915 | 0.4775
5821073 | 지상 6층 | 지상 6층 | 5821009 | 915 | 0.23875 | 0.00915 | 0.4775
5821074 | 지상 6층 | 지상 6층 | 5821009 | 300 | 0.085 | 0.003 | 0.16
5821075 | 지상 6층 | 지상 6층 | 5821009 | 600 | 0.16 | 0.006 | 0.3
5821076 | 지상 6층 | 지상 6층 | 5821009 | 1100 | 0.285 | 0.011 | 0.56
5821081 | 지상 6층 | 지상 6층 | 5821009 | 940 | 0.245 | 0.0094 | 0.48
5821082 | 지상 6층 | 지상 6층 | 5821009 | 940 | 0.245 | 0.0094 | 0.48
5821083 | 지상 6층 | 지상 6층 | 5821009 | 915 | 0.23875 | 0.00915 | 0.4775
5821084 | 지상 6층 | 지상 6층 | 5821009 | 915 | 0.23875 | 0.00915 | 0.4775
5821085 | 지상 6층 | 지상 6층 | 5821009 | 300 | 0.085 | 0.003 | 0.16
5821086 | 지상 6층 | 지상 6층 | 5821009 | 600 | 0.16 | 0.006 | 0.3
5821087 | 지상 6층 | 지상 6층 | 5821009 | 1100 | 0.285 | 0.011 | 0.56
5821092 | 지상 6층 | 지상 6층 | 5821009 | 970 | 0.2525 | 0.0097 | 0.495
5821093 | 지상 6층 | 지상 6층 | 5821009 | 1010 | 0.2625 | 0.0101 | 0.525
5821094 | 지상 6층 | 지상 6층 | 5821009 | 1010 | 0.2625 | 0.0101 | 0.525
5821095 | 지상 6층 | 지상 6층 | 5821009 | 1010 | 0.2625 | 0.0101 | 0.525
5821096 | 지상 6층 | 지상 6층 | 5821009 | 300 | 0.085 | 0.003 | 0.16
5821097 | 지상 6층 | 지상 6층 | 5821009 | 600 | 0.16 | 0.006 | 0.3
5821098 | 지상 6층 | 지상 6층 | 5821009 | 1100 | 0.285 | 0.011 | 0.56
5821103 | 지상 6층 | 지상 6층 | 5821009 | 1010 | 0.2625 | 0.0101 | 0.525
5821104 | 지상 6층 | 지상 6층 | 5821009 | 1080 | 0.28 | 0.0108 | 0.55
5821105 | 지상 6층 | 지상 6층 | 5821009 | 1055 | 0.27375 | 0.01055 | 0.5475
5821106 | 지상 6층 | 지상 6층 | 5821009 | 1055 | 0.27375 | 0.01055 | 0.5475
5821107 | 지상 6층 | 지상 6층 | 5821009 | 300 | 0.085 | 0.003 | 0.16
5821108 | 지상 6층 | 지상 6층 | 5821009 | 600 | 0.16 | 0.006 | 0.3
5821109 | 지상 6층 | 지상 6층 | 5821009 | 1100 | 0.285 | 0.011 | 0.56
5821114 | 지상 6층 | 지상 6층 | 5821009 | 1110 | 0.2875 | 0.0111 | 0.565
5821115 | 지상 6층 | 지상 6층 | 5821009 | 1010 | 0.2625 | 0.0101 | 0.525
5821116 | 지상 6층 | 지상 6층 | 5821009 | 1010 | 0.2625 | 0.0101 | 0.525
5821117 | 지상 6층 | 지상 6층 | 5821009 | 1010 | 0.2625 | 0.0101 | 0.525
5821118 | 지상 6층 | 지상 6층 | 5821009 | 300 | 0.085 | 0.003 | 0.16
5821119 | 지상 6층 | 지상 6층 | 5821009 | 600 | 0.16 | 0.006 | 0.3
5821120 | 지상 6층 | 지상 6층 | 5821009 | 1100 | 0.285 | 0.011 | 0.56
5821125 | 지상 6층 | 지상 6층 | 5821009 | 1010 | 0.2625 | 0.0101 | 0.525
5821126 | 지상 6층 | 지상 6층 | 5821009 | 940 | 0.245 | 0.0094 | 0.48
5821127 | 지상 6층 | 지상 6층 | 5821009 | 915 | 0.23875 | 0.00915 | 0.4775
5821128 | 지상 6층 | 지상 6층 | 5821009 | 915 | 0.23875 | 0.00915 | 0.4775
5821129 | 지상 6층 | 지상 6층 | 5821009 | 300 | 0.085 | 0.003 | 0.16
5821130 | 지상 6층 | 지상 6층 | 5821009 | 600 | 0.16 | 0.006 | 0.3
5821131 | 지상 6층 | 지상 6층 | 5821009 | 1100 | 0.285 | 0.011 | 0.56
5821136 | 지상 6층 | 지상 6층 | 5821009 | 940 | 0.245 | 0.0094 | 0.48
5821137 | 지상 6층 | 지상 6층 | 5821009 | 940 | 0.245 | 0.0094 | 0.48
5821138 | 지상 6층 | 지상 6층 | 5821009 | 915 | 0.23875 | 0.00915 | 0.4775
5821139 | 지상 6층 | 지상 6층 | 5821009 | 915 | 0.23875 | 0.00915 | 0.4775
5821140 | 지상 6층 | 지상 6층 | 5821009 | 300 | 0.085 | 0.003 | 0.16
5821141 | 지상 6층 | 지상 6층 | 5821009 | 600 | 0.16 | 0.006 | 0.3
5821142 | 지상 6층 | 지상 6층 | 5821009 | 1100 | 0.285 | 0.011 | 0.56
5821147 | 지상 6층 | 지상 6층 | 5821009 | 940 | 0.245 | 0.0094 | 0.48
5821148 | 지상 6층 | 지상 6층 | 5821009 | 940 | 0.245 | 0.0094 | 0.48
5821149 | 지상 6층 | 지상 6층 | 5821009 | 915 | 0.23875 | 0.00915 | 0.4775
5821150 | 지상 6층 | 지상 6층 | 5821009 | 915 | 0.23875 | 0.00915 | 0.4775
5821151 | 지상 6층 | 지상 6층 | 5821009 | 300 | 0.085 | 0.003 | 0.16
5821152 | 지상 6층 | 지상 6층 | 5821009 | 600 | 0.16 | 0.006 | 0.3
5821153 | 지상 6층 | 지상 6층 | 5821009 | 1100 | 0.285 | 0.011 | 0.56
5821158 | 지상 6층 | 지상 6층 | 5821009 | 940 | 0.245 | 0.0094 | 0.48
5821159 | 지상 6층 | 지상 6층 | 5821009 | 940 | 0.245 | 0.0094 | 0.48
5821160 | 지상 6층 | 지상 6층 | 5821009 | 915 | 0.23875 | 0.00915 | 0.4775
5821161 | 지상 6층 | 지상 6층 | 5821009 | 915 | 0.23875 | 0.00915 | 0.4775
5821162 | 지상 6층 | 지상 6층 | 5821009 | 300 | 0.085 | 0.003 | 0.16
5821163 | 지상 6층 | 지상 6층 | 5821009 | 600 | 0.16 | 0.006 | 0.3
5821164 | 지상 6층 | 지상 6층 | 5821009 | 1100 | 0.285 | 0.011 | 0.56
5821169 | 지상 6층 | 지상 6층 | 5821009 | 940 | 0.245 | 0.0094 | 0.48
5821170 | 지상 6층 | 지상 6층 | 5821009 | 940 | 0.245 | 0.0094 | 0.48
5821171 | 지상 6층 | 지상 6층 | 5821009 | 915 | 0.23875 | 0.00915 | 0.4775
5821172 | 지상 6층 | 지상 6층 | 5821009 | 915 | 0.23875 | 0.00915 | 0.4775
5821173 | 지상 6층 | 지상 6층 | 5821009 | 300 | 0.085 | 0.003 | 0.16
5821174 | 지상 6층 | 지상 6층 | 5821009 | 600 | 0.16 | 0.006 | 0.3
5821175 | 지상 6층 | 지상 6층 | 5821009 | 1100 | 0.285 | 0.011 | 0.56
5821180 | 지상 6층 | 지상 6층 | 5821009 | 935 | 0.24375 | 0.00935 | 0.4775
5821181 | 지상 6층 | 지상 6층 | 5821009 | 1010 | 0.2625 | 0.0101 | 0.525
5821182 | 지상 6층 | 지상 6층 | 5821009 | 1010 | 0.2625 | 0.0101 | 0.525
5821183 | 지상 6층 | 지상 6층 | 5821009 | 1010 | 0.2625 | 0.0101 | 0.525
5821184 | 지상 6층 | 지상 6층 | 5821009 | 300 | 0.085 | 0.003 | 0.16
5821185 | 지상 6층 | 지상 6층 | 5821009 | 600 | 0.16 | 0.006 | 0.3
5821186 | 지상 6층 | 지상 6층 | 5821009 | 1100 | 0.285 | 0.011 | 0.56
5821191 | 지상 6층 | 지상 6층 | 5821009 | 1010 | 0.2625 | 0.0101 | 0.525
5821192 | 지상 6층 | 지상 6층 | 5821009 | 995 | 0.25875 | 0.00995 | 0.5075
5821193 | 지상 6층 | 지상 6층 | 5821009 | 970 | 0.2525 | 0.0097 | 0.505
5821194 | 지상 6층 | 지상 6층 | 5821009 | 970 | 0.2525 | 0.0097 | 0.505
5821195 | 지상 6층 | 지상 6층 | 5821009 | 300 | 0.085 | 0.003 | 0.16
5821196 | 지상 6층 | 지상 6층 | 5821009 | 600 | 0.16 | 0.006 | 0.3
5821197 | 지상 6층 | 지상 6층 | 5821009 | 1100 | 0.285 | 0.011 | 0.56
5821202 | 지상 6층 | 지상 6층 | 5821009 | 940 | 0.245 | 0.0094 | 0.48
5821203 | 지상 6층 | 지상 6층 | 5821009 | 940 | 0.245 | 0.0094 | 0.48
5821204 | 지상 6층 | 지상 6층 | 5821009 | 915 | 0.23875 | 0.00915 | 0.4775
5821205 | 지상 6층 | 지상 6층 | 5821009 | 915 | 0.23875 | 0.00915 | 0.4775
5821206 | 지상 6층 | 지상 6층 | 5821009 | 300 | 0.085 | 0.003 | 0.16
5821207 | 지상 6층 | 지상 6층 | 5821009 | 600 | 0.16 | 0.006 | 0.3
5821208 | 지상 6층 | 지상 6층 | 5821009 | 1100 | 0.285 | 0.011 | 0.56
5821213 | 지상 6층 | 지상 6층 | 5821009 | 940 | 0.245 | 0.0094 | 0.48
5821214 | 지상 6층 | 지상 6층 | 5821009 | 940 | 0.245 | 0.0094 | 0.48
5821215 | 지상 6층 | 지상 6층 | 5821009 | 915 | 0.23875 | 0.00915 | 0.4775
5821216 | 지상 6층 | 지상 6층 | 5821009 | 915 | 0.23875 | 0.00915 | 0.4775
5821217 | 지상 6층 | 지상 6층 | 5821009 | 300 | 0.085 | 0.003 | 0.16
5821218 | 지상 6층 | 지상 6층 | 5821009 | 600 | 0.16 | 0.006 | 0.3
5821219 | 지상 6층 | 지상 6층 | 5821009 | 1100 | 0.285 | 0.011 | 0.56
5821224 | 지상 6층 | 지상 6층 | 5821009 | 940 | 0.245 | 0.0094 | 0.48
5821225 | 지상 6층 | 지상 6층 | 5821009 | 940 | 0.245 | 0.0094 | 0.48
5821226 | 지상 6층 | 지상 6층 | 5821009 | 915 | 0.23875 | 0.00915 | 0.4775
5821227 | 지상 6층 | 지상 6층 | 5821009 | 915 | 0.23875 | 0.00915 | 0.4775
5821228 | 지상 6층 | 지상 6층 | 5821009 | 300 | 0.085 | 0.003 | 0.16
5821229 | 지상 6층 | 지상 6층 | 5821009 | 600 | 0.16 | 0.006 | 0.3
5821230 | 지상 6층 | 지상 6층 | 5821009 | 1100 | 0.285 | 0.011 | 0.56
5821235 | 지상 6층 | 지상 6층 | 5821009 | 940 | 0.245 | 0.0094 | 0.48
5821236 | 지상 6층 | 지상 6층 | 5821009 | 1015 | 0.26375 | 0.01015 | 0.5275
5821237 | 지상 6층 | 지상 6층 | 5821009 | 1015 | 0.26375 | 0.01015 | 0.5275
5821238 | 지상 6층 | 지상 6층 | 5821009 | 1015 | 0.26375 | 0.01015 | 0.5275
5821239 | 지상 6층 | 지상 6층 | 5821009 | 300 | 0.085 | 0.003 | 0.16
5821240 | 지상 6층 | 지상 6층 | 5821009 | 600 | 0.16 | 0.006 | 0.3
5821241 | 지상 6층 | 지상 6층 | 5821009 | 1100 | 0.285 | 0.011 | 0.56
5821246 | 지상 6층 | 지상 6층 | 5821009 | 1015 | 0.26375 | 0.01015 | 0.5275
5821247 | 지상 6층 | 지상 6층 | 5821009 | 892.184 | 0.233046 | 0.00892184 | 0.466092
5821248 | 지상 6층 | 지상 6층 | 5821009 | 892.184 | 0.233046 | 0.00892184 | 0.466092
5821249 | 지상 6층 | 지상 6층 | 5821009 | 892.184 | 0.233046 | 0.00892184 | 0.466092
5821250 | 지상 6층 | 지상 6층 | 5821009 | 300 | 0.085 | 0.003 | 0.16
5821251 | 지상 6층 | 지상 6층 | 5821009 | 600 | 0.16 | 0.006 | 0.3
5821252 | 지상 6층 | 지상 6층 | 5821009 | 1100 | 0.285 | 0.011 | 0.56
5821257 | 지상 6층 | 지상 6층 | 5821009 | 970 | 0.2525 | 0.0097 | 0.495
5821258 | 지상 6층 | 지상 6층 | 5821009 | 940 | 0.245 | 0.0094 | 0.48
5821259 | 지상 6층 | 지상 6층 | 5821009 | 915 | 0.23875 | 0.00915 | 0.4775
5821260 | 지상 6층 | 지상 6층 | 5821009 | 915 | 0.23875 | 0.00915 | 0.4775
5821261 | 지상 6층 | 지상 6층 | 5821009 | 650 | 0.1725 | 0.0065 | 0.345
5821266 | 지상 6층 | 지상 6층 | 5821009 | 940 | 0.245 | 0.0094 | 0.48
5821267 | 지상 6층 | 지상 6층 | 5821009 | 915 | 0.23875 | 0.00915 | 0.4775
5821268 | 지상 6층 | 지상 6층 | 5821009 | 915 | 0.23875 | 0.00915 | 0.4775
5821269 | 지상 6층 | 지상 6층 | 5821009 | 940 | 0.245 | 0.0094 | 0.48
5821270 | 지상 6층 | 지상 6층 | 5821009 | 650 | 0.1725 | 0.0065 | 0.345
5821275 | 지상 6층 | 지상 6층 | 5821009 | 940 | 0.245 | 0.0094 | 0.48
5821276 | 지상 6층 | 지상 6층 | 5821009 | 915 | 0.23875 | 0.00915 | 0.4775
5821277 | 지상 6층 | 지상 6층 | 5821009 | 915 | 0.23875 | 0.00915 | 0.4775
5821278 | 지상 6층 | 지상 6층 | 5821009 | 940 | 0.245 | 0.0094 | 0.48
5821279 | 지상 6층 | 지상 6층 | 5821009 | 650 | 0.1725 | 0.0065 | 0.345
5821284 | 지상 6층 | 지상 6층 | 5821009 | 940 | 0.245 | 0.0094 | 0.48
5821285 | 지상 6층 | 지상 6층 | 5821009 | 915 | 0.23875 | 0.00915 | 0.4775
5821286 | 지상 6층 | 지상 6층 | 5821009 | 915 | 0.23875 | 0.00915 | 0.4775
5821287 | 지상 6층 | 지상 6층 | 5821009 | 940 | 0.245 | 0.0094 | 0.48
5821288 | 지상 6층 | 지상 6층 | 5821009 | 650 | 0.1725 | 0.0065 | 0.345
5821293 | 지상 6층 | 지상 6층 | 5821009 | 940 | 0.245 | 0.0094 | 0.48
5821294 | 지상 6층 | 지상 6층 | 5821009 | 915 | 0.23875 | 0.00915 | 0.4775
5821295 | 지상 6층 | 지상 6층 | 5821009 | 915 | 0.23875 | 0.00915 | 0.4775
5821296 | 지상 6층 | 지상 6층 | 5821009 | 940 | 0.245 | 0.0094 | 0.48
5821297 | 지상 6층 | 지상 6층 | 5821009 | 650 | 0.1725 | 0.0065 | 0.345
5821302 | 지상 6층 | 지상 6층 | 5821009 | 970 | 0.2525 | 0.0097 | 0.495
5821303 | 지상 6층 | 지상 6층 | 5821009 | 945 | 0.24625 | 0.00945 | 0.4925
5821304 | 지상 6층 | 지상 6층 | 5821009 | 945 | 0.24625 | 0.00945 | 0.4925
5821305 | 지상 6층 | 지상 6층 | 5821009 | 940 | 0.245 | 0.0094 | 0.48
5821306 | 지상 6층 | 지상 6층 | 5821009 | 650 | 0.1725 | 0.0065 | 0.345
5821311 | 지상 6층 | 지상 6층 | 5821009 | 1110 | 0.2875 | 0.0111 | 0.565
5821312 | 지상 6층 | 지상 6층 | 5821009 | 1085.02 | 0.281254 | 0.0108502 | 0.562508
5821313 | 지상 6층 | 지상 6층 | 5821009 | 1085.02 | 0.281254 | 0.0108502 | 0.562508
5821314 | 지상 6층 | 지상 6층 | 5821009 | 1080 | 0.28 | 0.0108 | 0.55
5821315 | 지상 6층 | 지상 6층 | 5821009 | 650 | 0.1725 | 0.0065 | 0.345
5821320 | 지상 6층 | 지상 6층 | 5821009 | 940 | 0.245 | 0.0094 | 0.48
5821321 | 지상 6층 | 지상 6층 | 5821009 | 915 | 0.23875 | 0.00915 | 0.4775
5821322 | 지상 6층 | 지상 6층 | 5821009 | 915 | 0.23875 | 0.00915 | 0.4775
5821323 | 지상 6층 | 지상 6층 | 5821009 | 940 | 0.245 | 0.0094 | 0.48
5821324 | 지상 6층 | 지상 6층 | 5821009 | 650 | 0.1725 | 0.0065 | 0.345
5821329 | 지상 6층 | 지상 6층 | 5821009 | 940 | 0.245 | 0.0094 | 0.48
5821330 | 지상 6층 | 지상 6층 | 5821009 | 915 | 0.23875 | 0.00915 | 0.4775
5821331 | 지상 6층 | 지상 6층 | 5821009 | 915 | 0.23875 | 0.00915 | 0.4775
5821332 | 지상 6층 | 지상 6층 | 5821009 | 940 | 0.245 | 0.0094 | 0.48
5821333 | 지상 6층 | 지상 6층 | 5821009 | 650 | 0.1725 | 0.0065 | 0.345
5821338 | 지상 6층 | 지상 6층 | 5821009 | 940 | 0.245 | 0.0094 | 0.48
5821339 | 지상 6층 | 지상 6층 | 5821009 | 915 | 0.23875 | 0.00915 | 0.4775
5821340 | 지상 6층 | 지상 6층 | 5821009 | 915 | 0.23875 | 0.00915 | 0.4775
5821341 | 지상 6층 | 지상 6층 | 5821009 | 940 | 0.245 | 0.0094 | 0.48
5821342 | 지상 6층 | 지상 6층 | 5821009 | 650 | 0.1725 | 0.0065 | 0.345
5821347 | 지상 6층 | 지상 6층 | 5821009 | 940 | 0.245 | 0.0094 | 0.48
5821348 | 지상 6층 | 지상 6층 | 5821009 | 915 | 0.23875 | 0.00915 | 0.4775
5821349 | 지상 6층 | 지상 6층 | 5821009 | 915 | 0.23875 | 0.00915 | 0.4775
5821350 | 지상 6층 | 지상 6층 | 5821009 | 940 | 0.245 | 0.0094 | 0.48
5821351 | 지상 6층 | 지상 6층 | 5821009 | 650 | 0.1725 | 0.0065 | 0.345
5821356 | 지상 6층 | 지상 6층 | 5821009 | 935 | 0.24375 | 0.00935 | 0.4775
5821357 | 지상 6층 | 지상 6층 | 5821009 | 910 | 0.2375 | 0.0091 | 0.475
5821358 | 지상 6층 | 지상 6층 | 5821009 | 910 | 0.2375 | 0.0091 | 0.475
5821359 | 지상 6층 | 지상 6층 | 5821009 | 940 | 0.245 | 0.0094 | 0.48
5821360 | 지상 6층 | 지상 6층 | 5821009 | 650 | 0.1725 | 0.0065 | 0.345
5821365 | 지상 6층 | 지상 6층 | 5821009 | 940 | 0.245 | 0.0094 | 0.48
5821366 | 지상 6층 | 지상 6층 | 5821009 | 915 | 0.23875 | 0.00915 | 0.4775
5821367 | 지상 6층 | 지상 6층 | 5821009 | 915 | 0.23875 | 0.00915 | 0.4775
5821368 | 지상 6층 | 지상 6층 | 5821009 | 995 | 0.25875 | 0.00995 | 0.5075
5821369 | 지상 6층 | 지상 6층 | 5821009 | 650 | 0.1725 | 0.0065 | 0.345
5821374 | 지상 6층 | 지상 6층 | 5821009 | 940 | 0.245 | 0.0094 | 0.48
5821375 | 지상 6층 | 지상 6층 | 5821009 | 915 | 0.23875 | 0.00915 | 0.4775
5821376 | 지상 6층 | 지상 6층 | 5821009 | 915 | 0.23875 | 0.00915 | 0.4775
5821377 | 지상 6층 | 지상 6층 | 5821009 | 940 | 0.245 | 0.0094 | 0.48
5821378 | 지상 6층 | 지상 6층 | 5821009 | 650 | 0.1725 | 0.0065 | 0.345
5821383 | 지상 6층 | 지상 6층 | 5821009 | 940 | 0.245 | 0.0094 | 0.48
5821384 | 지상 6층 | 지상 6층 | 5821009 | 915 | 0.23875 | 0.00915 | 0.4775
5821385 | 지상 6층 | 지상 6층 | 5821009 | 915 | 0.23875 | 0.00915 | 0.4775
5821386 | 지상 6층 | 지상 6층 | 5821009 | 940 | 0.245 | 0.0094 | 0.48
5821387 | 지상 6층 | 지상 6층 | 5821009 | 650 | 0.1725 | 0.0065 | 0.345
5821392 | 지상 6층 | 지상 6층 | 5821009 | 940 | 0.245 | 0.0094 | 0.48
5821393 | 지상 6층 | 지상 6층 | 5821009 | 915 | 0.23875 | 0.00915 | 0.4775
5821394 | 지상 6층 | 지상 6층 | 5821009 | 915 | 0.23875 | 0.00915 | 0.4775
5821395 | 지상 6층 | 지상 6층 | 5821009 | 940 | 0.245 | 0.0094 | 0.48
5821396 | 지상 6층 | 지상 6층 | 5821009 | 650 | 0.1725 | 0.0065 | 0.345
5821399 | 지상 6층 | 지상 6층 | 5821397 | 912.5 | 0.238125 | 0.009125 | 0.47625
5821400 | 지상 6층 | 지상 6층 | 5821397 | 178.395 | 0.0545986 | 0.00178395 | 0.109197
5821402 | 지상 6층 | 지상 6층 | 5821397 | 1100 | 0.285 | 0.011 | 0.56
5821406 | 지상 6층 | 지상 6층 | 5821397 | 300 | 0.085 | 0.003 | 0.16
5821407 | 지상 6층 | 지상 6층 | 5821397 | 178.395 | 0.0545986 | 0.00178395 | 0.109197
5821411 | 지상 6층 | 지상 6층 | 5821397 | 600 | 0.16 | 0.006 | 0.3
5821412 | 지상 6층 | 지상 6층 | 5821397 | 178.395 | 0.0545986 | 0.00178395 | 0.109197
5821417 | 지상 6층 | 지상 6층 | 5821397 | 178.395 | 0.0545986 | 0.00178395 | 0.109197
5821418 | 지상 6층 | 지상 6층 | 5821397 | 828.5 | 0.217125 | 0.008285 | 0.42425
5821419 | 지상 6층 | 지상 6층 | 5821397 | 803.5 | 0.210875 | 0.008035 | 0.42175
5821420 | 지상 6층 | 지상 6층 | 5821397 | 803.5 | 0.210875 | 0.008035 | 0.42175
5821421 | 지상 6층 | 지상 6층 | 5821397 | 300 | 0.085 | 0.003 | 0.16
5821422 | 지상 6층 | 지상 6층 | 5821397 | 600 | 0.16 | 0.006 | 0.3
5821423 | 지상 6층 | 지상 6층 | 5821397 | 1100 | 0.285 | 0.011 | 0.56
5821428 | 지상 6층 | 지상 6층 | 5821397 | 828.5 | 0.217125 | 0.008285 | 0.42425
5821429 | 지상 6층 | 지상 6층 | 5821397 | 828.5 | 0.217125 | 0.008285 | 0.42425
5821430 | 지상 6층 | 지상 6층 | 5821397 | 803.5 | 0.210875 | 0.008035 | 0.42175
5821431 | 지상 6층 | 지상 6층 | 5821397 | 803.5 | 0.210875 | 0.008035 | 0.42175
5821432 | 지상 6층 | 지상 6층 | 5821397 | 300 | 0.085 | 0.003 | 0.16
5821433 | 지상 6층 | 지상 6층 | 5821397 | 600 | 0.16 | 0.006 | 0.3
5821434 | 지상 6층 | 지상 6층 | 5821397 | 1100 | 0.285 | 0.011 | 0.56
5821439 | 지상 6층 | 지상 6층 | 5821397 | 828.5 | 0.217125 | 0.008285 | 0.42425
5821440 | 지상 6층 | 지상 6층 | 5821397 | 828.5 | 0.217125 | 0.008285 | 0.42425
5821441 | 지상 6층 | 지상 6층 | 5821397 | 803.5 | 0.210875 | 0.008035 | 0.42175
5821442 | 지상 6층 | 지상 6층 | 5821397 | 803.5 | 0.210875 | 0.008035 | 0.42175
5821443 | 지상 6층 | 지상 6층 | 5821397 | 300 | 0.085 | 0.003 | 0.16
5821444 | 지상 6층 | 지상 6층 | 5821397 | 600 | 0.16 | 0.006 | 0.3
5821445 | 지상 6층 | 지상 6층 | 5821397 | 1100 | 0.285 | 0.011 | 0.56
5821450 | 지상 6층 | 지상 6층 | 5821397 | 828.5 | 0.217125 | 0.008285 | 0.42425
5821451 | 지상 6층 | 지상 6층 | 5821397 | 828.5 | 0.217125 | 0.008285 | 0.42425
5821452 | 지상 6층 | 지상 6층 | 5821397 | 803.5 | 0.210875 | 0.008035 | 0.42175
5821453 | 지상 6층 | 지상 6층 | 5821397 | 803.5 | 0.210875 | 0.008035 | 0.42175
5821454 | 지상 6층 | 지상 6층 | 5821397 | 300 | 0.085 | 0.003 | 0.16
5821455 | 지상 6층 | 지상 6층 | 5821397 | 600 | 0.16 | 0.006 | 0.3
5821456 | 지상 6층 | 지상 6층 | 5821397 | 1100 | 0.285 | 0.011 | 0.56
5821461 | 지상 6층 | 지상 6층 | 5821397 | 828.5 | 0.217125 | 0.008285 | 0.42425
5821462 | 지상 6층 | 지상 6층 | 5821397 | 1120 | 0.29 | 0.0112 | 0.58
5821463 | 지상 6층 | 지상 6층 | 5821397 | 1120 | 0.29 | 0.0112 | 0.58
5821464 | 지상 6층 | 지상 6층 | 5821397 | 1120 | 0.29 | 0.0112 | 0.58
5821465 | 지상 6층 | 지상 6층 | 5821397 | 300 | 0.085 | 0.003 | 0.16
5821466 | 지상 6층 | 지상 6층 | 5821397 | 600 | 0.16 | 0.006 | 0.3
5821467 | 지상 6층 | 지상 6층 | 5821397 | 1100 | 0.285 | 0.011 | 0.56
5821472 | 지상 6층 | 지상 6층 | 5821397 | 1145 | 0.29625 | 0.01145 | 0.5825
5821473 | 지상 6층 | 지상 6층 | 5821397 | 754 | 0.1985 | 0.00754 | 0.387
5821474 | 지상 6층 | 지상 6층 | 5821397 | 729 | 0.19225 | 0.00729 | 0.3845
5821475 | 지상 6층 | 지상 6층 | 5821397 | 729 | 0.19225 | 0.00729 | 0.3845
5821476 | 지상 6층 | 지상 6층 | 5821397 | 300 | 0.085 | 0.003 | 0.16
5821477 | 지상 6층 | 지상 6층 | 5821397 | 600 | 0.16 | 0.006 | 0.3
5821478 | 지상 6층 | 지상 6층 | 5821397 | 1050 | 0.2725 | 0.0105 | 0.535
5821483 | 지상 6층 | 지상 6층 | 5821397 | 754 | 0.1985 | 0.00754 | 0.387
5821484 | 지상 6층 | 지상 6층 | 5821397 | 754 | 0.1985 | 0.00754 | 0.387
5821485 | 지상 6층 | 지상 6층 | 5821397 | 729 | 0.19225 | 0.00729 | 0.3845
5821486 | 지상 6층 | 지상 6층 | 5821397 | 729 | 0.19225 | 0.00729 | 0.3845
5821487 | 지상 6층 | 지상 6층 | 5821397 | 300 | 0.085 | 0.003 | 0.16
5821488 | 지상 6층 | 지상 6층 | 5821397 | 600 | 0.16 | 0.006 | 0.3
5821489 | 지상 6층 | 지상 6층 | 5821397 | 1100 | 0.285 | 0.011 | 0.56
5821494 | 지상 6층 | 지상 6층 | 5821397 | 754 | 0.1985 | 0.00754 | 0.387
5821495 | 지상 6층 | 지상 6층 | 5821397 | 754 | 0.1985 | 0.00754 | 0.387
5821496 | 지상 6층 | 지상 6층 | 5821397 | 729 | 0.19225 | 0.00729 | 0.3845
5821497 | 지상 6층 | 지상 6층 | 5821397 | 729 | 0.19225 | 0.00729 | 0.3845
5821498 | 지상 6층 | 지상 6층 | 5821397 | 300 | 0.085 | 0.003 | 0.16
5821499 | 지상 6층 | 지상 6층 | 5821397 | 600 | 0.16 | 0.006 | 0.3
5821500 | 지상 6층 | 지상 6층 | 5821397 | 1100 | 0.285 | 0.011 | 0.56
5821505 | 지상 6층 | 지상 6층 | 5821397 | 754 | 0.1985 | 0.00754 | 0.387
5821506 | 지상 6층 | 지상 6층 | 5821397 | 754 | 0.1985 | 0.00754 | 0.387
5821507 | 지상 6층 | 지상 6층 | 5821397 | 729 | 0.19225 | 0.00729 | 0.3845
5821508 | 지상 6층 | 지상 6층 | 5821397 | 729 | 0.19225 | 0.00729 | 0.3845
5821509 | 지상 6층 | 지상 6층 | 5821397 | 300 | 0.085 | 0.003 | 0.16
5821510 | 지상 6층 | 지상 6층 | 5821397 | 600 | 0.16 | 0.006 | 0.3
5821511 | 지상 6층 | 지상 6층 | 5821397 | 1100 | 0.285 | 0.011 | 0.56
5821516 | 지상 6층 | 지상 6층 | 5821397 | 754 | 0.1985 | 0.00754 | 0.387
5821517 | 지상 6층 | 지상 6층 | 5821397 | 1120 | 0.29 | 0.0112 | 0.58
5821518 | 지상 6층 | 지상 6층 | 5821397 | 1120 | 0.29 | 0.0112 | 0.58
5821519 | 지상 6층 | 지상 6층 | 5821397 | 1120 | 0.29 | 0.0112 | 0.58
5821520 | 지상 6층 | 지상 6층 | 5821397 | 300 | 0.085 | 0.003 | 0.16
5821521 | 지상 6층 | 지상 6층 | 5821397 | 600 | 0.16 | 0.006 | 0.3
5821522 | 지상 6층 | 지상 6층 | 5821397 | 1100 | 0.285 | 0.011 | 0.56
5821527 | 지상 6층 | 지상 6층 | 5821397 | 1120 | 0.29 | 0.0112 | 0.58
5821528 | 지상 6층 | 지상 6층 | 5821397 | 741.5 | 0.195375 | 0.007415 | 0.38075
5821529 | 지상 6층 | 지상 6층 | 5821397 | 716.5 | 0.189125 | 0.007165 | 0.37825
5821530 | 지상 6층 | 지상 6층 | 5821397 | 716.5 | 0.189125 | 0.007165 | 0.37825
5821531 | 지상 6층 | 지상 6층 | 5821397 | 300 | 0.085 | 0.003 | 0.16
5821532 | 지상 6층 | 지상 6층 | 5821397 | 600 | 0.16 | 0.006 | 0.3
5821533 | 지상 6층 | 지상 6층 | 5821397 | 1100 | 0.285 | 0.011 | 0.56
5821538 | 지상 6층 | 지상 6층 | 5821397 | 741.5 | 0.195375 | 0.007415 | 0.38075
5821539 | 지상 6층 | 지상 6층 | 5821397 | 741.5 | 0.195375 | 0.007415 | 0.38075
5821540 | 지상 6층 | 지상 6층 | 5821397 | 716.5 | 0.189125 | 0.007165 | 0.37825
5821541 | 지상 6층 | 지상 6층 | 5821397 | 716.5 | 0.189125 | 0.007165 | 0.37825
5821542 | 지상 6층 | 지상 6층 | 5821397 | 300 | 0.085 | 0.003 | 0.16
5821543 | 지상 6층 | 지상 6층 | 5821397 | 600 | 0.16 | 0.006 | 0.3
5821544 | 지상 6층 | 지상 6층 | 5821397 | 1100 | 0.285 | 0.011 | 0.56
5821549 | 지상 6층 | 지상 6층 | 5821397 | 741.5 | 0.195375 | 0.007415 | 0.38075
5821550 | 지상 6층 | 지상 6층 | 5821397 | 741.5 | 0.195375 | 0.007415 | 0.38075
5821551 | 지상 6층 | 지상 6층 | 5821397 | 716.5 | 0.189125 | 0.007165 | 0.37825
5821552 | 지상 6층 | 지상 6층 | 5821397 | 716.5 | 0.189125 | 0.007165 | 0.37825
5821553 | 지상 6층 | 지상 6층 | 5821397 | 300 | 0.085 | 0.003 | 0.16
5821554 | 지상 6층 | 지상 6층 | 5821397 | 600 | 0.16 | 0.006 | 0.3
5821555 | 지상 6층 | 지상 6층 | 5821397 | 1100 | 0.285 | 0.011 | 0.56
5821560 | 지상 6층 | 지상 6층 | 5821397 | 741.5 | 0.195375 | 0.007415 | 0.38075
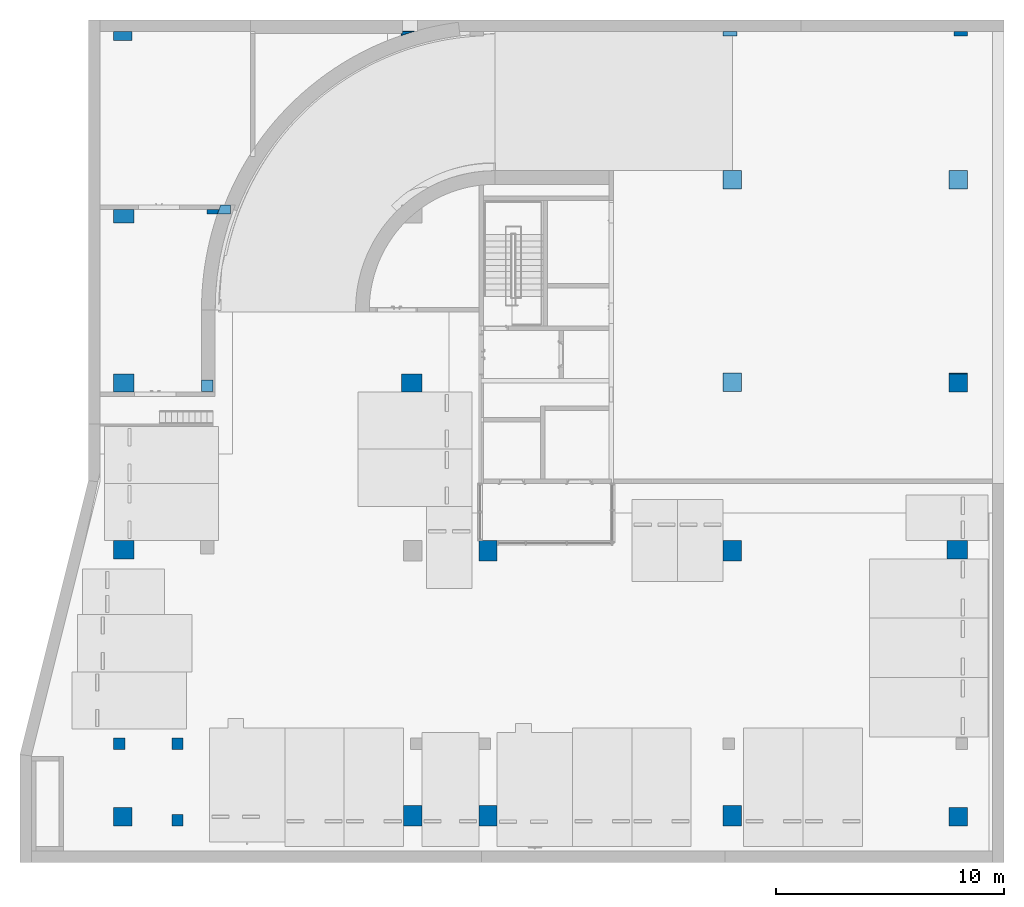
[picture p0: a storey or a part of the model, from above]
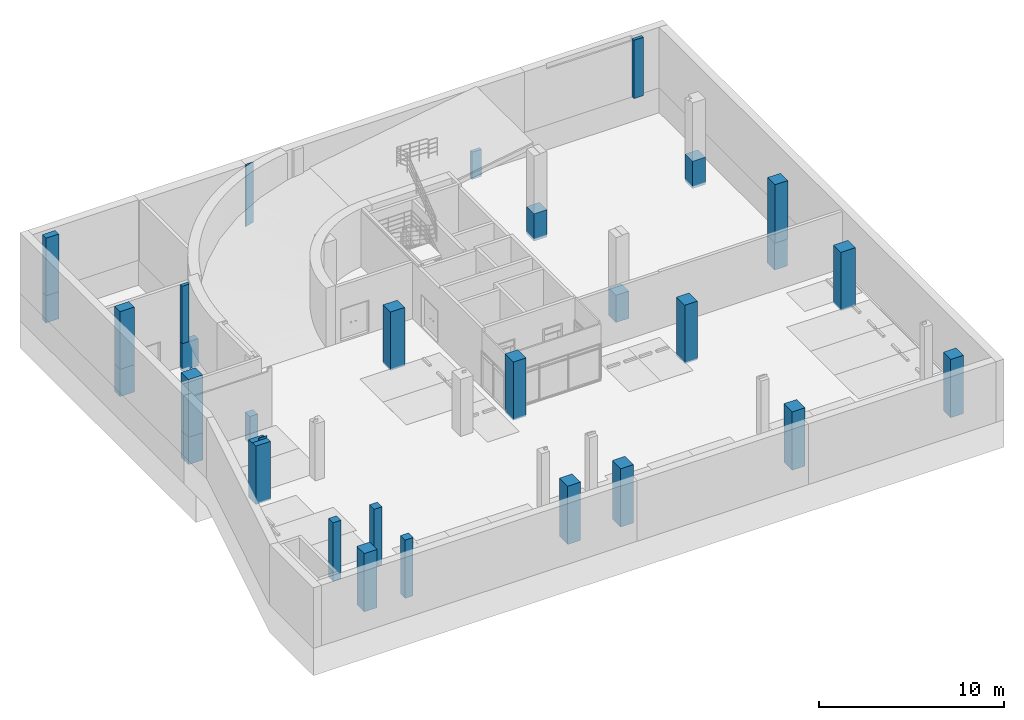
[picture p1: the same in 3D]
Properties of the parts of a building model (IFC2X3), part 23 of 39

# IfcMember: 직사각형 멀리언:CW200-직사각형 멀리언 50x200mm (8700)
Name (직사각형 멀리언:CW200-직사각형 멀리언 50x200mm:...) | In | 레벨 | 호스트 ID | 길이 (mm) = Span (mm) | 면적 (m2) = CrossSectionArea (m2) | 체적 (m3) = NetVolume (m3) | NetSurfaceArea (m2)
5821561 | 지상 6층 | 지상 6층 | 5821397 | 741.5 | 0.195375 | 0.007415 | 0.38075
5821562 | 지상 6층 | 지상 6층 | 5821397 | 716.5 | 0.189125 | 0.007165 | 0.37825
5821563 | 지상 6층 | 지상 6층 | 5821397 | 716.5 | 0.189125 | 0.007165 | 0.37825
5821564 | 지상 6층 | 지상 6층 | 5821397 | 300 | 0.085 | 0.003 | 0.16
5821565 | 지상 6층 | 지상 6층 | 5821397 | 600 | 0.16 | 0.006 | 0.3
5821566 | 지상 6층 | 지상 6층 | 5821397 | 1100 | 0.285 | 0.011 | 0.56
5821571 | 지상 6층 | 지상 6층 | 5821397 | 741.5 | 0.195375 | 0.007415 | 0.38075
5821572 | 지상 6층 | 지상 6층 | 5821397 | 1120 | 0.29 | 0.0112 | 0.58
5821573 | 지상 6층 | 지상 6층 | 5821397 | 1120 | 0.29 | 0.0112 | 0.58
5821574 | 지상 6층 | 지상 6층 | 5821397 | 1120 | 0.29 | 0.0112 | 0.58
5821575 | 지상 6층 | 지상 6층 | 5821397 | 300 | 0.085 | 0.003 | 0.16
5821576 | 지상 6층 | 지상 6층 | 5821397 | 600 | 0.16 | 0.006 | 0.3
5821577 | 지상 6층 | 지상 6층 | 5821397 | 1100 | 0.285 | 0.011 | 0.56
5821582 | 지상 6층 | 지상 6층 | 5821397 | 1120 | 0.29 | 0.0112 | 0.58
5821583 | 지상 6층 | 지상 6층 | 5821397 | 743.357 | 0.195839 | 0.00743357 | 0.381679
5821584 | 지상 6층 | 지상 6층 | 5821397 | 718.357 | 0.189589 | 0.00718357 | 0.379179
5821585 | 지상 6층 | 지상 6층 | 5821397 | 718.357 | 0.189589 | 0.00718357 | 0.379179
5821586 | 지상 6층 | 지상 6층 | 5821397 | 300 | 0.085 | 0.003 | 0.16
5821587 | 지상 6층 | 지상 6층 | 5821397 | 600 | 0.16 | 0.006 | 0.3
5821588 | 지상 6층 | 지상 6층 | 5821397 | 1100 | 0.285 | 0.011 | 0.56
5821593 | 지상 6층 | 지상 6층 | 5821397 | 743.357 | 0.195839 | 0.00743357 | 0.381679
5821594 | 지상 6층 | 지상 6층 | 5821397 | 743.357 | 0.195839 | 0.00743357 | 0.381679
5821595 | 지상 6층 | 지상 6층 | 5821397 | 718.357 | 0.189589 | 0.00718357 | 0.379179
5821596 | 지상 6층 | 지상 6층 | 5821397 | 718.357 | 0.189589 | 0.00718357 | 0.379179
5821597 | 지상 6층 | 지상 6층 | 5821397 | 300 | 0.085 | 0.003 | 0.16
5821598 | 지상 6층 | 지상 6층 | 5821397 | 600 | 0.16 | 0.006 | 0.3
5821599 | 지상 6층 | 지상 6층 | 5821397 | 1100 | 0.285 | 0.011 | 0.56
5821604 | 지상 6층 | 지상 6층 | 5821397 | 743.357 | 0.195839 | 0.00743357 | 0.381679
5821605 | 지상 6층 | 지상 6층 | 5821397 | 743.357 | 0.195839 | 0.00743357 | 0.381679
5821606 | 지상 6층 | 지상 6층 | 5821397 | 718.357 | 0.189589 | 0.00718357 | 0.379179
5821607 | 지상 6층 | 지상 6층 | 5821397 | 718.357 | 0.189589 | 0.00718357 | 0.379179
5821608 | 지상 6층 | 지상 6층 | 5821397 | 300 | 0.085 | 0.003 | 0.16
5821609 | 지상 6층 | 지상 6층 | 5821397 | 600 | 0.16 | 0.006 | 0.3
5821610 | 지상 6층 | 지상 6층 | 5821397 | 1100 | 0.285 | 0.011 | 0.56
5821615 | 지상 6층 | 지상 6층 | 5821397 | 743.357 | 0.195839 | 0.00743357 | 0.381679
5821616 | 지상 6층 | 지상 6층 | 5821397 | 743.357 | 0.195839 | 0.00743357 | 0.381679
5821617 | 지상 6층 | 지상 6층 | 5821397 | 718.357 | 0.189589 | 0.00718357 | 0.379179
5821618 | 지상 6층 | 지상 6층 | 5821397 | 718.357 | 0.189589 | 0.00718357 | 0.379179
5821619 | 지상 6층 | 지상 6층 | 5821397 | 300 | 0.085 | 0.003 | 0.16
5821620 | 지상 6층 | 지상 6층 | 5821397 | 600 | 0.16 | 0.006 | 0.3
5821621 | 지상 6층 | 지상 6층 | 5821397 | 1100 | 0.285 | 0.011 | 0.56
5821626 | 지상 6층 | 지상 6층 | 5821397 | 743.357 | 0.195839 | 0.00743357 | 0.381679
5821627 | 지상 6층 | 지상 6층 | 5821397 | 743.357 | 0.195839 | 0.00743357 | 0.381679
5821628 | 지상 6층 | 지상 6층 | 5821397 | 718.357 | 0.189589 | 0.00718357 | 0.379179
5821629 | 지상 6층 | 지상 6층 | 5821397 | 718.357 | 0.189589 | 0.00718357 | 0.379179
5821630 | 지상 6층 | 지상 6층 | 5821397 | 300 | 0.085 | 0.003 | 0.16
5821631 | 지상 6층 | 지상 6층 | 5821397 | 600 | 0.16 | 0.006 | 0.3
5821632 | 지상 6층 | 지상 6층 | 5821397 | 1100 | 0.285 | 0.011 | 0.56
5821637 | 지상 6층 | 지상 6층 | 5821397 | 743.357 | 0.195839 | 0.00743357 | 0.381679
5821638 | 지상 6층 | 지상 6층 | 5821397 | 743.357 | 0.195839 | 0.00743357 | 0.381679
5821639 | 지상 6층 | 지상 6층 | 5821397 | 718.357 | 0.189589 | 0.00718357 | 0.379179
5821640 | 지상 6층 | 지상 6층 | 5821397 | 718.357 | 0.189589 | 0.00718357 | 0.379179
5821641 | 지상 6층 | 지상 6층 | 5821397 | 300 | 0.085 | 0.003 | 0.16
5821642 | 지상 6층 | 지상 6층 | 5821397 | 600 | 0.16 | 0.006 | 0.3
5821643 | 지상 6층 | 지상 6층 | 5821397 | 1100 | 0.285 | 0.011 | 0.56
5821648 | 지상 6층 | 지상 6층 | 5821397 | 743.357 | 0.195839 | 0.00743357 | 0.381679
5821649 | 지상 6층 | 지상 6층 | 5821397 | 743.357 | 0.195839 | 0.00743357 | 0.381679
5821650 | 지상 6층 | 지상 6층 | 5821397 | 718.357 | 0.189589 | 0.00718357 | 0.379179
5821651 | 지상 6층 | 지상 6층 | 5821397 | 718.357 | 0.189589 | 0.00718357 | 0.379179
5821652 | 지상 6층 | 지상 6층 | 5821397 | 300 | 0.085 | 0.003 | 0.16
5821653 | 지상 6층 | 지상 6층 | 5821397 | 600 | 0.16 | 0.006 | 0.3
5821654 | 지상 6층 | 지상 6층 | 5821397 | 1100 | 0.285 | 0.011 | 0.56
5821659 | 지상 6층 | 지상 6층 | 5821397 | 743.357 | 0.195839 | 0.00743357 | 0.381679
5821660 | 지상 6층 | 지상 6층 | 5821397 | 912.5 | 0.238125 | 0.009125 | 0.47625
5821661 | 지상 6층 | 지상 6층 | 5821397 | 912.5 | 0.238125 | 0.009125 | 0.47625
5821662 | 지상 6층 | 지상 6층 | 5821397 | 912.5 | 0.238125 | 0.009125 | 0.47625
5821663 | 지상 6층 | 지상 6층 | 5821397 | 300 | 0.085 | 0.003 | 0.16
5821664 | 지상 6층 | 지상 6층 | 5821397 | 600 | 0.16 | 0.006 | 0.3
5821665 | 지상 6층 | 지상 6층 | 5821397 | 1100 | 0.285 | 0.011 | 0.56
5821670 | 지상 6층 | 지상 6층 | 5821397 | 828.5 | 0.217125 | 0.008285 | 0.42425
5821671 | 지상 6층 | 지상 6층 | 5821397 | 828.5 | 0.217125 | 0.008285 | 0.42425
5821672 | 지상 6층 | 지상 6층 | 5821397 | 803.5 | 0.210875 | 0.008035 | 0.42175
5821673 | 지상 6층 | 지상 6층 | 5821397 | 803.5 | 0.210875 | 0.008035 | 0.42175
5821674 | 지상 6층 | 지상 6층 | 5821397 | 650 | 0.1725 | 0.0065 | 0.345
5821679 | 지상 6층 | 지상 6층 | 5821397 | 828.5 | 0.217125 | 0.008285 | 0.42425
5821680 | 지상 6층 | 지상 6층 | 5821397 | 828.5 | 0.217125 | 0.008285 | 0.42425
5821681 | 지상 6층 | 지상 6층 | 5821397 | 803.5 | 0.210875 | 0.008035 | 0.42175
5821682 | 지상 6층 | 지상 6층 | 5821397 | 803.5 | 0.210875 | 0.008035 | 0.42175
5821683 | 지상 6층 | 지상 6층 | 5821397 | 650 | 0.1725 | 0.0065 | 0.345
5821688 | 지상 6층 | 지상 6층 | 5821397 | 828.5 | 0.217125 | 0.008285 | 0.42425
5821689 | 지상 6층 | 지상 6층 | 5821397 | 828.5 | 0.217125 | 0.008285 | 0.42425
5821690 | 지상 6층 | 지상 6층 | 5821397 | 803.5 | 0.210875 | 0.008035 | 0.42175
5821691 | 지상 6층 | 지상 6층 | 5821397 | 803.5 | 0.210875 | 0.008035 | 0.42175
5821692 | 지상 6층 | 지상 6층 | 5821397 | 650 | 0.1725 | 0.0065 | 0.345
5821697 | 지상 6층 | 지상 6층 | 5821397 | 828.5 | 0.217125 | 0.008285 | 0.42425
5821698 | 지상 6층 | 지상 6층 | 5821397 | 828.5 | 0.217125 | 0.008285 | 0.42425
5821699 | 지상 6층 | 지상 6층 | 5821397 | 803.5 | 0.210875 | 0.008035 | 0.42175
5821700 | 지상 6층 | 지상 6층 | 5821397 | 803.5 | 0.210875 | 0.008035 | 0.42175
5821701 | 지상 6층 | 지상 6층 | 5821397 | 650 | 0.1725 | 0.0065 | 0.345
5821706 | 지상 6층 | 지상 6층 | 5821397 | 779 | 0.20475 | 0.00779 | 0.3895
5821707 | 지상 6층 | 지상 6층 | 5821397 | 754 | 0.1985 | 0.00754 | 0.387
5821708 | 지상 6층 | 지상 6층 | 5821397 | 729 | 0.19225 | 0.00729 | 0.3845
5821709 | 지상 6층 | 지상 6층 | 5821397 | 729 | 0.19225 | 0.00729 | 0.3845
5821710 | 지상 6층 | 지상 6층 | 5821397 | 650 | 0.1725 | 0.0065 | 0.345
5821715 | 지상 6층 | 지상 6층 | 5821397 | 754 | 0.1985 | 0.00754 | 0.387
5821716 | 지상 6층 | 지상 6층 | 5821397 | 754 | 0.1985 | 0.00754 | 0.387
5821717 | 지상 6층 | 지상 6층 | 5821397 | 729 | 0.19225 | 0.00729 | 0.3845
5821718 | 지상 6층 | 지상 6층 | 5821397 | 729 | 0.19225 | 0.00729 | 0.3845
5821719 | 지상 6층 | 지상 6층 | 5821397 | 650 | 0.1725 | 0.0065 | 0.345
5821724 | 지상 6층 | 지상 6층 | 5821397 | 754 | 0.1985 | 0.00754 | 0.387
5821725 | 지상 6층 | 지상 6층 | 5821397 | 754 | 0.1985 | 0.00754 | 0.387
5821726 | 지상 6층 | 지상 6층 | 5821397 | 729 | 0.19225 | 0.00729 | 0.3845
5821727 | 지상 6층 | 지상 6층 | 5821397 | 729 | 0.19225 | 0.00729 | 0.3845
5821728 | 지상 6층 | 지상 6층 | 5821397 | 650 | 0.1725 | 0.0065 | 0.345
5821733 | 지상 6층 | 지상 6층 | 5821397 | 754 | 0.1985 | 0.00754 | 0.387
5821734 | 지상 6층 | 지상 6층 | 5821397 | 754 | 0.1985 | 0.00754 | 0.387
5821735 | 지상 6층 | 지상 6층 | 5821397 | 729 | 0.19225 | 0.00729 | 0.3845
5821736 | 지상 6층 | 지상 6층 | 5821397 | 729 | 0.19225 | 0.00729 | 0.3845
5821737 | 지상 6층 | 지상 6층 | 5821397 | 650 | 0.1725 | 0.0065 | 0.345
5821742 | 지상 6층 | 지상 6층 | 5821397 | 741.5 | 0.195375 | 0.007415 | 0.38075
5821743 | 지상 6층 | 지상 6층 | 5821397 | 741.5 | 0.195375 | 0.007415 | 0.38075
5821744 | 지상 6층 | 지상 6층 | 5821397 | 716.5 | 0.189125 | 0.007165 | 0.37825
5821745 | 지상 6층 | 지상 6층 | 5821397 | 716.5 | 0.189125 | 0.007165 | 0.37825
5821746 | 지상 6층 | 지상 6층 | 5821397 | 650 | 0.1725 | 0.0065 | 0.345
5821751 | 지상 6층 | 지상 6층 | 5821397 | 741.5 | 0.195375 | 0.007415 | 0.38075
5821752 | 지상 6층 | 지상 6층 | 5821397 | 741.5 | 0.195375 | 0.007415 | 0.38075
5821753 | 지상 6층 | 지상 6층 | 5821397 | 716.5 | 0.189125 | 0.007165 | 0.37825
5821754 | 지상 6층 | 지상 6층 | 5821397 | 716.5 | 0.189125 | 0.007165 | 0.37825
5821755 | 지상 6층 | 지상 6층 | 5821397 | 650 | 0.1725 | 0.0065 | 0.345
5821760 | 지상 6층 | 지상 6층 | 5821397 | 741.5 | 0.195375 | 0.007415 | 0.38075
5821761 | 지상 6층 | 지상 6층 | 5821397 | 741.5 | 0.195375 | 0.007415 | 0.38075
5821762 | 지상 6층 | 지상 6층 | 5821397 | 716.5 | 0.189125 | 0.007165 | 0.37825
5821763 | 지상 6층 | 지상 6층 | 5821397 | 716.5 | 0.189125 | 0.007165 | 0.37825
5821764 | 지상 6층 | 지상 6층 | 5821397 | 650 | 0.1725 | 0.0065 | 0.345
5821769 | 지상 6층 | 지상 6층 | 5821397 | 741.5 | 0.195375 | 0.007415 | 0.38075
5821770 | 지상 6층 | 지상 6층 | 5821397 | 741.5 | 0.195375 | 0.007415 | 0.38075
5821771 | 지상 6층 | 지상 6층 | 5821397 | 716.5 | 0.189125 | 0.007165 | 0.37825
5821772 | 지상 6층 | 지상 6층 | 5821397 | 716.5 | 0.189125 | 0.007165 | 0.37825
5821773 | 지상 6층 | 지상 6층 | 5821397 | 650 | 0.1725 | 0.0065 | 0.345
5821778 | 지상 6층 | 지상 6층 | 5821397 | 743.357 | 0.195839 | 0.00743357 | 0.381679
5821779 | 지상 6층 | 지상 6층 | 5821397 | 743.357 | 0.195839 | 0.00743357 | 0.381679
5821780 | 지상 6층 | 지상 6층 | 5821397 | 718.357 | 0.189589 | 0.00718357 | 0.379179
5821781 | 지상 6층 | 지상 6층 | 5821397 | 718.357 | 0.189589 | 0.00718357 | 0.379179
5821782 | 지상 6층 | 지상 6층 | 5821397 | 650 | 0.1725 | 0.0065 | 0.345
5821787 | 지상 6층 | 지상 6층 | 5821397 | 743.357 | 0.195839 | 0.00743357 | 0.381679
5821788 | 지상 6층 | 지상 6층 | 5821397 | 743.357 | 0.195839 | 0.00743357 | 0.381679
5821789 | 지상 6층 | 지상 6층 | 5821397 | 718.357 | 0.189589 | 0.00718357 | 0.379179
5821790 | 지상 6층 | 지상 6층 | 5821397 | 718.357 | 0.189589 | 0.00718357 | 0.379179
5821791 | 지상 6층 | 지상 6층 | 5821397 | 650 | 0.1725 | 0.0065 | 0.345
5821796 | 지상 6층 | 지상 6층 | 5821397 | 743.357 | 0.195839 | 0.00743357 | 0.381679
5821797 | 지상 6층 | 지상 6층 | 5821397 | 743.357 | 0.195839 | 0.00743357 | 0.381679
5821798 | 지상 6층 | 지상 6층 | 5821397 | 718.357 | 0.189589 | 0.00718357 | 0.379179
5821799 | 지상 6층 | 지상 6층 | 5821397 | 718.357 | 0.189589 | 0.00718357 | 0.379179
5821800 | 지상 6층 | 지상 6층 | 5821397 | 650 | 0.1725 | 0.0065 | 0.345
5821805 | 지상 6층 | 지상 6층 | 5821397 | 743.357 | 0.195839 | 0.00743357 | 0.381679
5821806 | 지상 6층 | 지상 6층 | 5821397 | 743.357 | 0.195839 | 0.00743357 | 0.381679
5821807 | 지상 6층 | 지상 6층 | 5821397 | 718.357 | 0.189589 | 0.00718357 | 0.379179
5821808 | 지상 6층 | 지상 6층 | 5821397 | 718.357 | 0.189589 | 0.00718357 | 0.379179
5821809 | 지상 6층 | 지상 6층 | 5821397 | 650 | 0.1725 | 0.0065 | 0.345
5821814 | 지상 6층 | 지상 6층 | 5821397 | 743.357 | 0.195839 | 0.00743357 | 0.381679
5821815 | 지상 6층 | 지상 6층 | 5821397 | 743.357 | 0.195839 | 0.00743357 | 0.381679
5821816 | 지상 6층 | 지상 6층 | 5821397 | 718.357 | 0.189589 | 0.00718357 | 0.379179
5821817 | 지상 6층 | 지상 6층 | 5821397 | 718.357 | 0.189589 | 0.00718357 | 0.379179
5821818 | 지상 6층 | 지상 6층 | 5821397 | 650 | 0.1725 | 0.0065 | 0.345
5821823 | 지상 6층 | 지상 6층 | 5821397 | 743.357 | 0.195839 | 0.00743357 | 0.381679
5821824 | 지상 6층 | 지상 6층 | 5821397 | 743.357 | 0.195839 | 0.00743357 | 0.381679
5821825 | 지상 6층 | 지상 6층 | 5821397 | 718.357 | 0.189589 | 0.00718357 | 0.379179
5821826 | 지상 6층 | 지상 6층 | 5821397 | 718.357 | 0.189589 | 0.00718357 | 0.379179
5821827 | 지상 6층 | 지상 6층 | 5821397 | 650 | 0.1725 | 0.0065 | 0.345
5821832 | 지상 6층 | 지상 6층 | 5821397 | 743.357 | 0.195839 | 0.00743357 | 0.381679
5821833 | 지상 6층 | 지상 6층 | 5821397 | 743.357 | 0.195839 | 0.00743357 | 0.381679
5821834 | 지상 6층 | 지상 6층 | 5821397 | 718.357 | 0.189589 | 0.00718357 | 0.379179
5821835 | 지상 6층 | 지상 6층 | 5821397 | 718.357 | 0.189589 | 0.00718357 | 0.379179
5821836 | 지상 6층 | 지상 6층 | 5821397 | 650 | 0.1725 | 0.0065 | 0.345
5821880 | 지상 5층 | 지상 5층 | 5821878 | 892.184 | 0.233046 | 0.00892184 | 0.466092
5821881 | 지상 5층 | 지상 5층 | 5821878 | 912.816 | 0.238204 | 0.00912816 | 0.476408
5821886 | 지상 5층 | 지상 5층 | 5821878 | 912.816 | 0.238204 | 0.00912816 | 0.476408
5821890 | 지상 5층 | 지상 5층 | 5821878 | 912.816 | 0.238204 | 0.00912816 | 0.476408
5821895 | 지상 5층 | 지상 5층 | 5821878 | 912.816 | 0.238204 | 0.00912816 | 0.476408
5821896 | 지상 5층 | 지상 5층 | 5821878 | 970 | 0.2525 | 0.0097 | 0.495
5821897 | 지상 5층 | 지상 5층 | 5821878 | 945 | 0.24625 | 0.00945 | 0.4925
5821898 | 지상 5층 | 지상 5층 | 5821878 | 945 | 0.24625 | 0.00945 | 0.4925
5821899 | 지상 5층 | 지상 5층 | 5821878 | 300 | 0.085 | 0.003 | 0.16
5821900 | 지상 5층 | 지상 5층 | 5821878 | 600 | 0.16 | 0.006 | 0.3
5821901 | 지상 5층 | 지상 5층 | 5821878 | 1100 | 0.285 | 0.011 | 0.56
5821906 | 지상 5층 | 지상 5층 | 5821878 | 940 | 0.245 | 0.0094 | 0.48
5821907 | 지상 5층 | 지상 5층 | 5821878 | 940 | 0.245 | 0.0094 | 0.48
5821908 | 지상 5층 | 지상 5층 | 5821878 | 915 | 0.23875 | 0.00915 | 0.4775
5821909 | 지상 5층 | 지상 5층 | 5821878 | 915 | 0.23875 | 0.00915 | 0.4775
5821910 | 지상 5층 | 지상 5층 | 5821878 | 300 | 0.085 | 0.003 | 0.16
5821911 | 지상 5층 | 지상 5층 | 5821878 | 600 | 0.16 | 0.006 | 0.3
5821912 | 지상 5층 | 지상 5층 | 5821878 | 1100 | 0.285 | 0.011 | 0.56
5821917 | 지상 5층 | 지상 5층 | 5821878 | 940 | 0.245 | 0.0094 | 0.48
5821918 | 지상 5층 | 지상 5층 | 5821878 | 940 | 0.245 | 0.0094 | 0.48
5821919 | 지상 5층 | 지상 5층 | 5821878 | 915 | 0.23875 | 0.00915 | 0.4775
5821920 | 지상 5층 | 지상 5층 | 5821878 | 915 | 0.23875 | 0.00915 | 0.4775
5821921 | 지상 5층 | 지상 5층 | 5821878 | 300 | 0.085 | 0.003 | 0.16
5821922 | 지상 5층 | 지상 5층 | 5821878 | 600 | 0.16 | 0.006 | 0.3
5821923 | 지상 5층 | 지상 5층 | 5821878 | 1100 | 0.285 | 0.011 | 0.56
5821928 | 지상 5층 | 지상 5층 | 5821878 | 940 | 0.245 | 0.0094 | 0.48
5821929 | 지상 5층 | 지상 5층 | 5821878 | 940 | 0.245 | 0.0094 | 0.48
5821930 | 지상 5층 | 지상 5층 | 5821878 | 915 | 0.23875 | 0.00915 | 0.4775
5821931 | 지상 5층 | 지상 5층 | 5821878 | 915 | 0.23875 | 0.00915 | 0.4775
5821932 | 지상 5층 | 지상 5층 | 5821878 | 300 | 0.085 | 0.003 | 0.16
5821933 | 지상 5층 | 지상 5층 | 5821878 | 600 | 0.16 | 0.006 | 0.3
5821934 | 지상 5층 | 지상 5층 | 5821878 | 1100 | 0.285 | 0.011 | 0.56
5821939 | 지상 5층 | 지상 5층 | 5821878 | 940 | 0.245 | 0.0094 | 0.48
5821940 | 지상 5층 | 지상 5층 | 5821878 | 940 | 0.245 | 0.0094 | 0.48
5821941 | 지상 5층 | 지상 5층 | 5821878 | 915 | 0.23875 | 0.00915 | 0.4775
5821942 | 지상 5층 | 지상 5층 | 5821878 | 915 | 0.23875 | 0.00915 | 0.4775
5821943 | 지상 5층 | 지상 5층 | 5821878 | 300 | 0.085 | 0.003 | 0.16
5821944 | 지상 5층 | 지상 5층 | 5821878 | 600 | 0.16 | 0.006 | 0.3
5821945 | 지상 5층 | 지상 5층 | 5821878 | 1100 | 0.285 | 0.011 | 0.56
5821950 | 지상 5층 | 지상 5층 | 5821878 | 940 | 0.245 | 0.0094 | 0.48
5821951 | 지상 5층 | 지상 5층 | 5821878 | 940 | 0.245 | 0.0094 | 0.48
5821952 | 지상 5층 | 지상 5층 | 5821878 | 915 | 0.23875 | 0.00915 | 0.4775
5821953 | 지상 5층 | 지상 5층 | 5821878 | 915 | 0.23875 | 0.00915 | 0.4775
5821954 | 지상 5층 | 지상 5층 | 5821878 | 300 | 0.085 | 0.003 | 0.16
5821955 | 지상 5층 | 지상 5층 | 5821878 | 600 | 0.16 | 0.006 | 0.3
5821956 | 지상 5층 | 지상 5층 | 5821878 | 1100 | 0.285 | 0.011 | 0.56
5821961 | 지상 5층 | 지상 5층 | 5821878 | 970 | 0.2525 | 0.0097 | 0.495
5821962 | 지상 5층 | 지상 5층 | 5821878 | 1010 | 0.2625 | 0.0101 | 0.525
5821963 | 지상 5층 | 지상 5층 | 5821878 | 1010 | 0.2625 | 0.0101 | 0.525
5821964 | 지상 5층 | 지상 5층 | 5821878 | 1010 | 0.2625 | 0.0101 | 0.525
5821965 | 지상 5층 | 지상 5층 | 5821878 | 300 | 0.085 | 0.003 | 0.16
5821966 | 지상 5층 | 지상 5층 | 5821878 | 600 | 0.16 | 0.006 | 0.3
5821967 | 지상 5층 | 지상 5층 | 5821878 | 1100 | 0.285 | 0.011 | 0.56
5821972 | 지상 5층 | 지상 5층 | 5821878 | 1010 | 0.2625 | 0.0101 | 0.525
5821973 | 지상 5층 | 지상 5층 | 5821878 | 1080 | 0.28 | 0.0108 | 0.55
5821974 | 지상 5층 | 지상 5층 | 5821878 | 1055 | 0.27375 | 0.01055 | 0.5475
5821975 | 지상 5층 | 지상 5층 | 5821878 | 1055 | 0.27375 | 0.01055 | 0.5475
5821976 | 지상 5층 | 지상 5층 | 5821878 | 300 | 0.085 | 0.003 | 0.16
5821977 | 지상 5층 | 지상 5층 | 5821878 | 600 | 0.16 | 0.006 | 0.3
5821978 | 지상 5층 | 지상 5층 | 5821878 | 1100 | 0.285 | 0.011 | 0.56
5821983 | 지상 5층 | 지상 5층 | 5821878 | 1110 | 0.2875 | 0.0111 | 0.565
5821984 | 지상 5층 | 지상 5층 | 5821878 | 1010 | 0.2625 | 0.0101 | 0.525
5821985 | 지상 5층 | 지상 5층 | 5821878 | 1010 | 0.2625 | 0.0101 | 0.525
5821986 | 지상 5층 | 지상 5층 | 5821878 | 1010 | 0.2625 | 0.0101 | 0.525
5821987 | 지상 5층 | 지상 5층 | 5821878 | 300 | 0.085 | 0.003 | 0.16
5821988 | 지상 5층 | 지상 5층 | 5821878 | 600 | 0.16 | 0.006 | 0.3
5821989 | 지상 5층 | 지상 5층 | 5821878 | 1100 | 0.285 | 0.011 | 0.56
5821994 | 지상 5층 | 지상 5층 | 5821878 | 1010 | 0.2625 | 0.0101 | 0.525
5821995 | 지상 5층 | 지상 5층 | 5821878 | 940 | 0.245 | 0.0094 | 0.48
5821996 | 지상 5층 | 지상 5층 | 5821878 | 915 | 0.23875 | 0.00915 | 0.4775
5821997 | 지상 5층 | 지상 5층 | 5821878 | 915 | 0.23875 | 0.00915 | 0.4775
5821998 | 지상 5층 | 지상 5층 | 5821878 | 300 | 0.085 | 0.003 | 0.16
5821999 | 지상 5층 | 지상 5층 | 5821878 | 600 | 0.16 | 0.006 | 0.3
5822000 | 지상 5층 | 지상 5층 | 5821878 | 1100 | 0.285 | 0.011 | 0.56
5822005 | 지상 5층 | 지상 5층 | 5821878 | 940 | 0.245 | 0.0094 | 0.48
5822006 | 지상 5층 | 지상 5층 | 5821878 | 940 | 0.245 | 0.0094 | 0.48
5822007 | 지상 5층 | 지상 5층 | 5821878 | 915 | 0.23875 | 0.00915 | 0.4775
5822008 | 지상 5층 | 지상 5층 | 5821878 | 915 | 0.23875 | 0.00915 | 0.4775
5822009 | 지상 5층 | 지상 5층 | 5821878 | 300 | 0.085 | 0.003 | 0.16
5822010 | 지상 5층 | 지상 5층 | 5821878 | 600 | 0.16 | 0.006 | 0.3
5822011 | 지상 5층 | 지상 5층 | 5821878 | 1100 | 0.285 | 0.011 | 0.56
5822016 | 지상 5층 | 지상 5층 | 5821878 | 940 | 0.245 | 0.0094 | 0.48
5822017 | 지상 5층 | 지상 5층 | 5821878 | 940 | 0.245 | 0.0094 | 0.48
5822018 | 지상 5층 | 지상 5층 | 5821878 | 915 | 0.23875 | 0.00915 | 0.4775
5822019 | 지상 5층 | 지상 5층 | 5821878 | 915 | 0.23875 | 0.00915 | 0.4775
5822020 | 지상 5층 | 지상 5층 | 5821878 | 300 | 0.085 | 0.003 | 0.16
5822021 | 지상 5층 | 지상 5층 | 5821878 | 600 | 0.16 | 0.006 | 0.3
5822022 | 지상 5층 | 지상 5층 | 5821878 | 1100 | 0.285 | 0.011 | 0.56
5822027 | 지상 5층 | 지상 5층 | 5821878 | 940 | 0.245 | 0.0094 | 0.48
5822028 | 지상 5층 | 지상 5층 | 5821878 | 940 | 0.245 | 0.0094 | 0.48
5822029 | 지상 5층 | 지상 5층 | 5821878 | 915 | 0.23875 | 0.00915 | 0.4775
5822030 | 지상 5층 | 지상 5층 | 5821878 | 915 | 0.23875 | 0.00915 | 0.4775
5822031 | 지상 5층 | 지상 5층 | 5821878 | 300 | 0.085 | 0.003 | 0.16
5822032 | 지상 5층 | 지상 5층 | 5821878 | 600 | 0.16 | 0.006 | 0.3
5822033 | 지상 5층 | 지상 5층 | 5821878 | 1100 | 0.285 | 0.011 | 0.56
5822038 | 지상 5층 | 지상 5층 | 5821878 | 940 | 0.245 | 0.0094 | 0.48
5822039 | 지상 5층 | 지상 5층 | 5821878 | 940 | 0.245 | 0.0094 | 0.48
5822040 | 지상 5층 | 지상 5층 | 5821878 | 915 | 0.23875 | 0.00915 | 0.4775
5822041 | 지상 5층 | 지상 5층 | 5821878 | 915 | 0.23875 | 0.00915 | 0.4775
5822042 | 지상 5층 | 지상 5층 | 5821878 | 300 | 0.085 | 0.003 | 0.16
5822043 | 지상 5층 | 지상 5층 | 5821878 | 600 | 0.16 | 0.006 | 0.3
5822044 | 지상 5층 | 지상 5층 | 5821878 | 1100 | 0.285 | 0.011 | 0.56
5822049 | 지상 5층 | 지상 5층 | 5821878 | 935 | 0.24375 | 0.00935 | 0.4775
5822050 | 지상 5층 | 지상 5층 | 5821878 | 1010 | 0.2625 | 0.0101 | 0.525
5822051 | 지상 5층 | 지상 5층 | 5821878 | 1010 | 0.2625 | 0.0101 | 0.525
5822052 | 지상 5층 | 지상 5층 | 5821878 | 1010 | 0.2625 | 0.0101 | 0.525
5822053 | 지상 5층 | 지상 5층 | 5821878 | 300 | 0.085 | 0.003 | 0.16
5822054 | 지상 5층 | 지상 5층 | 5821878 | 600 | 0.16 | 0.006 | 0.3
5822055 | 지상 5층 | 지상 5층 | 5821878 | 1100 | 0.285 | 0.011 | 0.56
5822060 | 지상 5층 | 지상 5층 | 5821878 | 1010 | 0.2625 | 0.0101 | 0.525
5822061 | 지상 5층 | 지상 5층 | 5821878 | 995 | 0.25875 | 0.00995 | 0.5075
5822062 | 지상 5층 | 지상 5층 | 5821878 | 970 | 0.2525 | 0.0097 | 0.505
5822063 | 지상 5층 | 지상 5층 | 5821878 | 970 | 0.2525 | 0.0097 | 0.505
5822064 | 지상 5층 | 지상 5층 | 5821878 | 300 | 0.085 | 0.003 | 0.16
5822065 | 지상 5층 | 지상 5층 | 5821878 | 600 | 0.16 | 0.006 | 0.3
5822066 | 지상 5층 | 지상 5층 | 5821878 | 1100 | 0.285 | 0.011 | 0.56
5822071 | 지상 5층 | 지상 5층 | 5821878 | 940 | 0.245 | 0.0094 | 0.48
5822072 | 지상 5층 | 지상 5층 | 5821878 | 940 | 0.245 | 0.0094 | 0.48
5822073 | 지상 5층 | 지상 5층 | 5821878 | 915 | 0.23875 | 0.00915 | 0.4775
5822074 | 지상 5층 | 지상 5층 | 5821878 | 915 | 0.23875 | 0.00915 | 0.4775
5822075 | 지상 5층 | 지상 5층 | 5821878 | 300 | 0.085 | 0.003 | 0.16
5822076 | 지상 5층 | 지상 5층 | 5821878 | 600 | 0.16 | 0.006 | 0.3
5822077 | 지상 5층 | 지상 5층 | 5821878 | 1100 | 0.285 | 0.011 | 0.56
5822082 | 지상 5층 | 지상 5층 | 5821878 | 940 | 0.245 | 0.0094 | 0.48
5822083 | 지상 5층 | 지상 5층 | 5821878 | 940 | 0.245 | 0.0094 | 0.48
5822084 | 지상 5층 | 지상 5층 | 5821878 | 915 | 0.23875 | 0.00915 | 0.4775
5822085 | 지상 5층 | 지상 5층 | 5821878 | 915 | 0.23875 | 0.00915 | 0.4775
5822086 | 지상 5층 | 지상 5층 | 5821878 | 300 | 0.085 | 0.003 | 0.16
5822087 | 지상 5층 | 지상 5층 | 5821878 | 600 | 0.16 | 0.006 | 0.3
5822088 | 지상 5층 | 지상 5층 | 5821878 | 1100 | 0.285 | 0.011 | 0.56
5822093 | 지상 5층 | 지상 5층 | 5821878 | 940 | 0.245 | 0.0094 | 0.48
5822094 | 지상 5층 | 지상 5층 | 5821878 | 940 | 0.245 | 0.0094 | 0.48
5822095 | 지상 5층 | 지상 5층 | 5821878 | 915 | 0.23875 | 0.00915 | 0.4775
5822096 | 지상 5층 | 지상 5층 | 5821878 | 915 | 0.23875 | 0.00915 | 0.4775
5822097 | 지상 5층 | 지상 5층 | 5821878 | 300 | 0.085 | 0.003 | 0.16
5822098 | 지상 5층 | 지상 5층 | 5821878 | 600 | 0.16 | 0.006 | 0.3
5822099 | 지상 5층 | 지상 5층 | 5821878 | 1100 | 0.285 | 0.011 | 0.56
5822104 | 지상 5층 | 지상 5층 | 5821878 | 940 | 0.245 | 0.0094 | 0.48
5822105 | 지상 5층 | 지상 5층 | 5821878 | 1015 | 0.26375 | 0.01015 | 0.5275
5822106 | 지상 5층 | 지상 5층 | 5821878 | 1015 | 0.26375 | 0.01015 | 0.5275
5822107 | 지상 5층 | 지상 5층 | 5821878 | 1015 | 0.26375 | 0.01015 | 0.5275
5822108 | 지상 5층 | 지상 5층 | 5821878 | 300 | 0.085 | 0.003 | 0.16
5822109 | 지상 5층 | 지상 5층 | 5821878 | 600 | 0.16 | 0.006 | 0.3
5822110 | 지상 5층 | 지상 5층 | 5821878 | 1100 | 0.285 | 0.011 | 0.56
5822115 | 지상 5층 | 지상 5층 | 5821878 | 1015 | 0.26375 | 0.01015 | 0.5275
5822116 | 지상 5층 | 지상 5층 | 5821878 | 892.184 | 0.233046 | 0.00892184 | 0.466092
5822117 | 지상 5층 | 지상 5층 | 5821878 | 892.184 | 0.233046 | 0.00892184 | 0.466092
5822118 | 지상 5층 | 지상 5층 | 5821878 | 892.184 | 0.233046 | 0.00892184 | 0.466092
5822119 | 지상 5층 | 지상 5층 | 5821878 | 300 | 0.085 | 0.003 | 0.16
5822120 | 지상 5층 | 지상 5층 | 5821878 | 600 | 0.16 | 0.006 | 0.3
5822121 | 지상 5층 | 지상 5층 | 5821878 | 1100 | 0.285 | 0.011 | 0.56
5822126 | 지상 5층 | 지상 5층 | 5821878 | 970 | 0.2525 | 0.0097 | 0.495
5822127 | 지상 5층 | 지상 5층 | 5821878 | 940 | 0.245 | 0.0094 | 0.48
5822128 | 지상 5층 | 지상 5층 | 5821878 | 915 | 0.23875 | 0.00915 | 0.4775
5822129 | 지상 5층 | 지상 5층 | 5821878 | 915 | 0.23875 | 0.00915 | 0.4775
5822130 | 지상 5층 | 지상 5층 | 5821878 | 650 | 0.1725 | 0.0065 | 0.345
5822135 | 지상 5층 | 지상 5층 | 5821878 | 940 | 0.245 | 0.0094 | 0.48
5822136 | 지상 5층 | 지상 5층 | 5821878 | 915 | 0.23875 | 0.00915 | 0.4775
5822137 | 지상 5층 | 지상 5층 | 5821878 | 915 | 0.23875 | 0.00915 | 0.4775
5822138 | 지상 5층 | 지상 5층 | 5821878 | 940 | 0.245 | 0.0094 | 0.48
5822139 | 지상 5층 | 지상 5층 | 5821878 | 650 | 0.1725 | 0.0065 | 0.345
5822144 | 지상 5층 | 지상 5층 | 5821878 | 940 | 0.245 | 0.0094 | 0.48
5822145 | 지상 5층 | 지상 5층 | 5821878 | 915 | 0.23875 | 0.00915 | 0.4775
5822146 | 지상 5층 | 지상 5층 | 5821878 | 915 | 0.23875 | 0.00915 | 0.4775
5822147 | 지상 5층 | 지상 5층 | 5821878 | 940 | 0.245 | 0.0094 | 0.48
5822148 | 지상 5층 | 지상 5층 | 5821878 | 650 | 0.1725 | 0.0065 | 0.345
5822153 | 지상 5층 | 지상 5층 | 5821878 | 940 | 0.245 | 0.0094 | 0.48
5822154 | 지상 5층 | 지상 5층 | 5821878 | 915 | 0.23875 | 0.00915 | 0.4775
5822155 | 지상 5층 | 지상 5층 | 5821878 | 915 | 0.23875 | 0.00915 | 0.4775
5822156 | 지상 5층 | 지상 5층 | 5821878 | 940 | 0.245 | 0.0094 | 0.48
5822157 | 지상 5층 | 지상 5층 | 5821878 | 650 | 0.1725 | 0.0065 | 0.345
5822162 | 지상 5층 | 지상 5층 | 5821878 | 940 | 0.245 | 0.0094 | 0.48
5822163 | 지상 5층 | 지상 5층 | 5821878 | 915 | 0.23875 | 0.00915 | 0.4775
5822164 | 지상 5층 | 지상 5층 | 5821878 | 915 | 0.23875 | 0.00915 | 0.4775
5822165 | 지상 5층 | 지상 5층 | 5821878 | 940 | 0.245 | 0.0094 | 0.48
5822166 | 지상 5층 | 지상 5층 | 5821878 | 650 | 0.1725 | 0.0065 | 0.345
5822171 | 지상 5층 | 지상 5층 | 5821878 | 970 | 0.2525 | 0.0097 | 0.495
5822172 | 지상 5층 | 지상 5층 | 5821878 | 945 | 0.24625 | 0.00945 | 0.4925
5822173 | 지상 5층 | 지상 5층 | 5821878 | 945 | 0.24625 | 0.00945 | 0.4925
5822174 | 지상 5층 | 지상 5층 | 5821878 | 940 | 0.245 | 0.0094 | 0.48
5822175 | 지상 5층 | 지상 5층 | 5821878 | 650 | 0.1725 | 0.0065 | 0.345
5822180 | 지상 5층 | 지상 5층 | 5821878 | 1110 | 0.2875 | 0.0111 | 0.565
5822181 | 지상 5층 | 지상 5층 | 5821878 | 1085.02 | 0.281254 | 0.0108502 | 0.562508
5822182 | 지상 5층 | 지상 5층 | 5821878 | 1085.02 | 0.281254 | 0.0108502 | 0.562508
5822183 | 지상 5층 | 지상 5층 | 5821878 | 1080 | 0.28 | 0.0108 | 0.55
5822184 | 지상 5층 | 지상 5층 | 5821878 | 650 | 0.1725 | 0.0065 | 0.345
5822189 | 지상 5층 | 지상 5층 | 5821878 | 940 | 0.245 | 0.0094 | 0.48
5822190 | 지상 5층 | 지상 5층 | 5821878 | 915 | 0.23875 | 0.00915 | 0.4775
5822191 | 지상 5층 | 지상 5층 | 5821878 | 915 | 0.23875 | 0.00915 | 0.4775
5822192 | 지상 5층 | 지상 5층 | 5821878 | 940 | 0.245 | 0.0094 | 0.48
5822193 | 지상 5층 | 지상 5층 | 5821878 | 650 | 0.1725 | 0.0065 | 0.345
5822198 | 지상 5층 | 지상 5층 | 5821878 | 940 | 0.245 | 0.0094 | 0.48
5822199 | 지상 5층 | 지상 5층 | 5821878 | 915 | 0.23875 | 0.00915 | 0.4775
5822200 | 지상 5층 | 지상 5층 | 5821878 | 915 | 0.23875 | 0.00915 | 0.4775
5822201 | 지상 5층 | 지상 5층 | 5821878 | 940 | 0.245 | 0.0094 | 0.48
5822202 | 지상 5층 | 지상 5층 | 5821878 | 650 | 0.1725 | 0.0065 | 0.345
5822207 | 지상 5층 | 지상 5층 | 5821878 | 940 | 0.245 | 0.0094 | 0.48
5822208 | 지상 5층 | 지상 5층 | 5821878 | 915 | 0.23875 | 0.00915 | 0.4775
5822209 | 지상 5층 | 지상 5층 | 5821878 | 915 | 0.23875 | 0.00915 | 0.4775
5822210 | 지상 5층 | 지상 5층 | 5821878 | 940 | 0.245 | 0.0094 | 0.48
5822211 | 지상 5층 | 지상 5층 | 5821878 | 650 | 0.1725 | 0.0065 | 0.345
5822216 | 지상 5층 | 지상 5층 | 5821878 | 940 | 0.245 | 0.0094 | 0.48
5822217 | 지상 5층 | 지상 5층 | 5821878 | 915 | 0.23875 | 0.00915 | 0.4775
5822218 | 지상 5층 | 지상 5층 | 5821878 | 915 | 0.23875 | 0.00915 | 0.4775
5822219 | 지상 5층 | 지상 5층 | 5821878 | 940 | 0.245 | 0.0094 | 0.48
5822220 | 지상 5층 | 지상 5층 | 5821878 | 650 | 0.1725 | 0.0065 | 0.345
5822225 | 지상 5층 | 지상 5층 | 5821878 | 935 | 0.24375 | 0.00935 | 0.4775
5822226 | 지상 5층 | 지상 5층 | 5821878 | 910 | 0.2375 | 0.0091 | 0.475
5822227 | 지상 5층 | 지상 5층 | 5821878 | 910 | 0.2375 | 0.0091 | 0.475
5822228 | 지상 5층 | 지상 5층 | 5821878 | 940 | 0.245 | 0.0094 | 0.48
5822229 | 지상 5층 | 지상 5층 | 5821878 | 650 | 0.1725 | 0.0065 | 0.345
5822234 | 지상 5층 | 지상 5층 | 5821878 | 940 | 0.245 | 0.0094 | 0.48
5822235 | 지상 5층 | 지상 5층 | 5821878 | 915 | 0.23875 | 0.00915 | 0.4775
5822236 | 지상 5층 | 지상 5층 | 5821878 | 915 | 0.23875 | 0.00915 | 0.4775
5822237 | 지상 5층 | 지상 5층 | 5821878 | 995 | 0.25875 | 0.00995 | 0.5075
5822238 | 지상 5층 | 지상 5층 | 5821878 | 650 | 0.1725 | 0.0065 | 0.345
5822243 | 지상 5층 | 지상 5층 | 5821878 | 940 | 0.245 | 0.0094 | 0.48
5822244 | 지상 5층 | 지상 5층 | 5821878 | 915 | 0.23875 | 0.00915 | 0.4775
5822245 | 지상 5층 | 지상 5층 | 5821878 | 915 | 0.23875 | 0.00915 | 0.4775
5822246 | 지상 5층 | 지상 5층 | 5821878 | 940 | 0.245 | 0.0094 | 0.48
5822247 | 지상 5층 | 지상 5층 | 5821878 | 650 | 0.1725 | 0.0065 | 0.345
5822252 | 지상 5층 | 지상 5층 | 5821878 | 940 | 0.245 | 0.0094 | 0.48
5822253 | 지상 5층 | 지상 5층 | 5821878 | 915 | 0.23875 | 0.00915 | 0.4775
5822254 | 지상 5층 | 지상 5층 | 5821878 | 915 | 0.23875 | 0.00915 | 0.4775
5822255 | 지상 5층 | 지상 5층 | 5821878 | 940 | 0.245 | 0.0094 | 0.48
5822256 | 지상 5층 | 지상 5층 | 5821878 | 650 | 0.1725 | 0.0065 | 0.345
5822261 | 지상 5층 | 지상 5층 | 5821878 | 940 | 0.245 | 0.0094 | 0.48
5822262 | 지상 5층 | 지상 5층 | 5821878 | 915 | 0.23875 | 0.00915 | 0.4775
5822263 | 지상 5층 | 지상 5층 | 5821878 | 915 | 0.23875 | 0.00915 | 0.4775
5822264 | 지상 5층 | 지상 5층 | 5821878 | 940 | 0.245 | 0.0094 | 0.48
5822265 | 지상 5층 | 지상 5층 | 5821878 | 650 | 0.1725 | 0.0065 | 0.345
5822268 | 지상 5층 | 지상 5층 | 5822266 | 912.5 | 0.238125 | 0.009125 | 0.47625
5822269 | 지상 5층 | 지상 5층 | 5822266 | 178.395 | 0.0545986 | 0.00178395 | 0.109197
5822271 | 지상 5층 | 지상 5층 | 5822266 | 1100 | 0.285 | 0.011 | 0.56
5822275 | 지상 5층 | 지상 5층 | 5822266 | 300 | 0.085 | 0.003 | 0.16
5822276 | 지상 5층 | 지상 5층 | 5822266 | 178.395 | 0.0545986 | 0.00178395 | 0.109197
5822280 | 지상 5층 | 지상 5층 | 5822266 | 600 | 0.16 | 0.006 | 0.3
5822281 | 지상 5층 | 지상 5층 | 5822266 | 178.395 | 0.0545986 | 0.00178395 | 0.109197
5822286 | 지상 5층 | 지상 5층 | 5822266 | 178.395 | 0.0545986 | 0.00178395 | 0.109197
5822287 | 지상 5층 | 지상 5층 | 5822266 | 828.5 | 0.217125 | 0.008285 | 0.42425
5822288 | 지상 5층 | 지상 5층 | 5822266 | 803.5 | 0.210875 | 0.008035 | 0.42175
5822289 | 지상 5층 | 지상 5층 | 5822266 | 803.5 | 0.210875 | 0.008035 | 0.42175
5822290 | 지상 5층 | 지상 5층 | 5822266 | 300 | 0.085 | 0.003 | 0.16
5822291 | 지상 5층 | 지상 5층 | 5822266 | 600 | 0.16 | 0.006 | 0.3
5822292 | 지상 5층 | 지상 5층 | 5822266 | 1100 | 0.285 | 0.011 | 0.56
5822297 | 지상 5층 | 지상 5층 | 5822266 | 828.5 | 0.217125 | 0.008285 | 0.42425
5822298 | 지상 5층 | 지상 5층 | 5822266 | 828.5 | 0.217125 | 0.008285 | 0.42425
5822299 | 지상 5층 | 지상 5층 | 5822266 | 803.5 | 0.210875 | 0.008035 | 0.42175
5822300 | 지상 5층 | 지상 5층 | 5822266 | 803.5 | 0.210875 | 0.008035 | 0.42175
5822301 | 지상 5층 | 지상 5층 | 5822266 | 300 | 0.085 | 0.003 | 0.16
5822302 | 지상 5층 | 지상 5층 | 5822266 | 600 | 0.16 | 0.006 | 0.3
5822303 | 지상 5층 | 지상 5층 | 5822266 | 1100 | 0.285 | 0.011 | 0.56
5822308 | 지상 5층 | 지상 5층 | 5822266 | 828.5 | 0.217125 | 0.008285 | 0.42425
5822309 | 지상 5층 | 지상 5층 | 5822266 | 828.5 | 0.217125 | 0.008285 | 0.42425
5822310 | 지상 5층 | 지상 5층 | 5822266 | 803.5 | 0.210875 | 0.008035 | 0.42175
5822311 | 지상 5층 | 지상 5층 | 5822266 | 803.5 | 0.210875 | 0.008035 | 0.42175
5822312 | 지상 5층 | 지상 5층 | 5822266 | 300 | 0.085 | 0.003 | 0.16
5822313 | 지상 5층 | 지상 5층 | 5822266 | 600 | 0.16 | 0.006 | 0.3
5822314 | 지상 5층 | 지상 5층 | 5822266 | 1100 | 0.285 | 0.011 | 0.56
5822319 | 지상 5층 | 지상 5층 | 5822266 | 828.5 | 0.217125 | 0.008285 | 0.42425
5822320 | 지상 5층 | 지상 5층 | 5822266 | 828.5 | 0.217125 | 0.008285 | 0.42425
5822321 | 지상 5층 | 지상 5층 | 5822266 | 803.5 | 0.210875 | 0.008035 | 0.42175
5822322 | 지상 5층 | 지상 5층 | 5822266 | 803.5 | 0.210875 | 0.008035 | 0.42175
5822323 | 지상 5층 | 지상 5층 | 5822266 | 300 | 0.085 | 0.003 | 0.16
5822324 | 지상 5층 | 지상 5층 | 5822266 | 600 | 0.16 | 0.006 | 0.3
5822325 | 지상 5층 | 지상 5층 | 5822266 | 1100 | 0.285 | 0.011 | 0.56
5822330 | 지상 5층 | 지상 5층 | 5822266 | 828.5 | 0.217125 | 0.008285 | 0.42425
5822331 | 지상 5층 | 지상 5층 | 5822266 | 1120 | 0.29 | 0.0112 | 0.58
5822332 | 지상 5층 | 지상 5층 | 5822266 | 1120 | 0.29 | 0.0112 | 0.58
5822333 | 지상 5층 | 지상 5층 | 5822266 | 1120 | 0.29 | 0.0112 | 0.58
5822334 | 지상 5층 | 지상 5층 | 5822266 | 300 | 0.085 | 0.003 | 0.16
5822335 | 지상 5층 | 지상 5층 | 5822266 | 600 | 0.16 | 0.006 | 0.3
5822336 | 지상 5층 | 지상 5층 | 5822266 | 1100 | 0.285 | 0.011 | 0.56
5822341 | 지상 5층 | 지상 5층 | 5822266 | 1120 | 0.29 | 0.0112 | 0.58
5822342 | 지상 5층 | 지상 5층 | 5822266 | 754 | 0.1985 | 0.00754 | 0.387
5822343 | 지상 5층 | 지상 5층 | 5822266 | 729 | 0.19225 | 0.00729 | 0.3845
5822344 | 지상 5층 | 지상 5층 | 5822266 | 729 | 0.19225 | 0.00729 | 0.3845
5822345 | 지상 5층 | 지상 5층 | 5822266 | 300 | 0.085 | 0.003 | 0.16
5822346 | 지상 5층 | 지상 5층 | 5822266 | 600 | 0.16 | 0.006 | 0.3
5822347 | 지상 5층 | 지상 5층 | 5822266 | 1100 | 0.285 | 0.011 | 0.56
5822352 | 지상 5층 | 지상 5층 | 5822266 | 754 | 0.1985 | 0.00754 | 0.387
5822353 | 지상 5층 | 지상 5층 | 5822266 | 754 | 0.1985 | 0.00754 | 0.387
5822354 | 지상 5층 | 지상 5층 | 5822266 | 729 | 0.19225 | 0.00729 | 0.3845
5822355 | 지상 5층 | 지상 5층 | 5822266 | 729 | 0.19225 | 0.00729 | 0.3845
5822356 | 지상 5층 | 지상 5층 | 5822266 | 300 | 0.085 | 0.003 | 0.16
5822357 | 지상 5층 | 지상 5층 | 5822266 | 600 | 0.16 | 0.006 | 0.3
5822358 | 지상 5층 | 지상 5층 | 5822266 | 1100 | 0.285 | 0.011 | 0.56
5822363 | 지상 5층 | 지상 5층 | 5822266 | 754 | 0.1985 | 0.00754 | 0.387
5822364 | 지상 5층 | 지상 5층 | 5822266 | 754 | 0.1985 | 0.00754 | 0.387
5822365 | 지상 5층 | 지상 5층 | 5822266 | 729 | 0.19225 | 0.00729 | 0.3845
5822366 | 지상 5층 | 지상 5층 | 5822266 | 729 | 0.19225 | 0.00729 | 0.3845
5822367 | 지상 5층 | 지상 5층 | 5822266 | 300 | 0.085 | 0.003 | 0.16
5822368 | 지상 5층 | 지상 5층 | 5822266 | 600 | 0.16 | 0.006 | 0.3
5822369 | 지상 5층 | 지상 5층 | 5822266 | 1100 | 0.285 | 0.011 | 0.56
5822374 | 지상 5층 | 지상 5층 | 5822266 | 754 | 0.1985 | 0.00754 | 0.387
5822375 | 지상 5층 | 지상 5층 | 5822266 | 754 | 0.1985 | 0.00754 | 0.387
5822376 | 지상 5층 | 지상 5층 | 5822266 | 729 | 0.19225 | 0.00729 | 0.3845
5822377 | 지상 5층 | 지상 5층 | 5822266 | 729 | 0.19225 | 0.00729 | 0.3845
5822378 | 지상 5층 | 지상 5층 | 5822266 | 300 | 0.085 | 0.003 | 0.16
5822379 | 지상 5층 | 지상 5층 | 5822266 | 600 | 0.16 | 0.006 | 0.3
5822380 | 지상 5층 | 지상 5층 | 5822266 | 1100 | 0.285 | 0.011 | 0.56
5822385 | 지상 5층 | 지상 5층 | 5822266 | 754 | 0.1985 | 0.00754 | 0.387
5822386 | 지상 5층 | 지상 5층 | 5822266 | 1120 | 0.29 | 0.0112 | 0.58
5822387 | 지상 5층 | 지상 5층 | 5822266 | 1120 | 0.29 | 0.0112 | 0.58
5822388 | 지상 5층 | 지상 5층 | 5822266 | 1120 | 0.29 | 0.0112 | 0.58
5822389 | 지상 5층 | 지상 5층 | 5822266 | 300 | 0.085 | 0.003 | 0.16
5822390 | 지상 5층 | 지상 5층 | 5822266 | 600 | 0.16 | 0.006 | 0.3
5822391 | 지상 5층 | 지상 5층 | 5822266 | 1100 | 0.285 | 0.011 | 0.56
5822396 | 지상 5층 | 지상 5층 | 5822266 | 1120 | 0.29 | 0.0112 | 0.58
5822397 | 지상 5층 | 지상 5층 | 5822266 | 741.5 | 0.195375 | 0.007415 | 0.38075
5822398 | 지상 5층 | 지상 5층 | 5822266 | 716.5 | 0.189125 | 0.007165 | 0.37825
5822399 | 지상 5층 | 지상 5층 | 5822266 | 716.5 | 0.189125 | 0.007165 | 0.37825
5822400 | 지상 5층 | 지상 5층 | 5822266 | 300 | 0.085 | 0.003 | 0.16
5822401 | 지상 5층 | 지상 5층 | 5822266 | 600 | 0.16 | 0.006 | 0.3
5822402 | 지상 5층 | 지상 5층 | 5822266 | 1100 | 0.285 | 0.011 | 0.56
5822407 | 지상 5층 | 지상 5층 | 5822266 | 741.5 | 0.195375 | 0.007415 | 0.38075
5822408 | 지상 5층 | 지상 5층 | 5822266 | 741.5 | 0.195375 | 0.007415 | 0.38075
5822409 | 지상 5층 | 지상 5층 | 5822266 | 716.5 | 0.189125 | 0.007165 | 0.37825
5822410 | 지상 5층 | 지상 5층 | 5822266 | 716.5 | 0.189125 | 0.007165 | 0.37825
5822411 | 지상 5층 | 지상 5층 | 5822266 | 300 | 0.085 | 0.003 | 0.16
5822412 | 지상 5층 | 지상 5층 | 5822266 | 600 | 0.16 | 0.006 | 0.3
5822413 | 지상 5층 | 지상 5층 | 5822266 | 1100 | 0.285 | 0.011 | 0.56
5822418 | 지상 5층 | 지상 5층 | 5822266 | 741.5 | 0.195375 | 0.007415 | 0.38075
5822419 | 지상 5층 | 지상 5층 | 5822266 | 741.5 | 0.195375 | 0.007415 | 0.38075
5822420 | 지상 5층 | 지상 5층 | 5822266 | 716.5 | 0.189125 | 0.007165 | 0.37825
5822421 | 지상 5층 | 지상 5층 | 5822266 | 716.5 | 0.189125 | 0.007165 | 0.37825
5822422 | 지상 5층 | 지상 5층 | 5822266 | 300 | 0.085 | 0.003 | 0.16
5822423 | 지상 5층 | 지상 5층 | 5822266 | 600 | 0.16 | 0.006 | 0.3
5822424 | 지상 5층 | 지상 5층 | 5822266 | 1100 | 0.285 | 0.011 | 0.56
5822429 | 지상 5층 | 지상 5층 | 5822266 | 741.5 | 0.195375 | 0.007415 | 0.38075
5822430 | 지상 5층 | 지상 5층 | 5822266 | 741.5 | 0.195375 | 0.007415 | 0.38075
5822431 | 지상 5층 | 지상 5층 | 5822266 | 716.5 | 0.189125 | 0.007165 | 0.37825
5822432 | 지상 5층 | 지상 5층 | 5822266 | 716.5 | 0.189125 | 0.007165 | 0.37825
5822433 | 지상 5층 | 지상 5층 | 5822266 | 300 | 0.085 | 0.003 | 0.16
5822434 | 지상 5층 | 지상 5층 | 5822266 | 600 | 0.16 | 0.006 | 0.3
5822435 | 지상 5층 | 지상 5층 | 5822266 | 1100 | 0.285 | 0.011 | 0.56
5822440 | 지상 5층 | 지상 5층 | 5822266 | 741.5 | 0.195375 | 0.007415 | 0.38075
5822441 | 지상 5층 | 지상 5층 | 5822266 | 1120 | 0.29 | 0.0112 | 0.58
5822442 | 지상 5층 | 지상 5층 | 5822266 | 1120 | 0.29 | 0.0112 | 0.58
5822443 | 지상 5층 | 지상 5층 | 5822266 | 1120 | 0.29 | 0.0112 | 0.58
5822444 | 지상 5층 | 지상 5층 | 5822266 | 300 | 0.085 | 0.003 | 0.16
5822445 | 지상 5층 | 지상 5층 | 5822266 | 600 | 0.16 | 0.006 | 0.3
5822446 | 지상 5층 | 지상 5층 | 5822266 | 1100 | 0.285 | 0.011 | 0.56
5822451 | 지상 5층 | 지상 5층 | 5822266 | 1120 | 0.29 | 0.0112 | 0.58
5822452 | 지상 5층 | 지상 5층 | 5822266 | 743.357 | 0.195839 | 0.00743357 | 0.381679
5822453 | 지상 5층 | 지상 5층 | 5822266 | 718.357 | 0.189589 | 0.00718357 | 0.379179
5822454 | 지상 5층 | 지상 5층 | 5822266 | 718.357 | 0.189589 | 0.00718357 | 0.379179
5822455 | 지상 5층 | 지상 5층 | 5822266 | 300 | 0.085 | 0.003 | 0.16
5822456 | 지상 5층 | 지상 5층 | 5822266 | 600 | 0.16 | 0.006 | 0.3
5822457 | 지상 5층 | 지상 5층 | 5822266 | 1100 | 0.285 | 0.011 | 0.56
5822462 | 지상 5층 | 지상 5층 | 5822266 | 743.357 | 0.195839 | 0.00743357 | 0.381679
5822463 | 지상 5층 | 지상 5층 | 5822266 | 743.357 | 0.195839 | 0.00743357 | 0.381679
5822464 | 지상 5층 | 지상 5층 | 5822266 | 718.357 | 0.189589 | 0.00718357 | 0.379179
5822465 | 지상 5층 | 지상 5층 | 5822266 | 718.357 | 0.189589 | 0.00718357 | 0.379179
5822466 | 지상 5층 | 지상 5층 | 5822266 | 300 | 0.085 | 0.003 | 0.16
5822467 | 지상 5층 | 지상 5층 | 5822266 | 600 | 0.16 | 0.006 | 0.3
5822468 | 지상 5층 | 지상 5층 | 5822266 | 1100 | 0.285 | 0.011 | 0.56
5822473 | 지상 5층 | 지상 5층 | 5822266 | 743.357 | 0.195839 | 0.00743357 | 0.381679
5822474 | 지상 5층 | 지상 5층 | 5822266 | 743.357 | 0.195839 | 0.00743357 | 0.381679
5822475 | 지상 5층 | 지상 5층 | 5822266 | 718.357 | 0.189589 | 0.00718357 | 0.379179
5822476 | 지상 5층 | 지상 5층 | 5822266 | 718.357 | 0.189589 | 0.00718357 | 0.379179
5822477 | 지상 5층 | 지상 5층 | 5822266 | 300 | 0.085 | 0.003 | 0.16
5822478 | 지상 5층 | 지상 5층 | 5822266 | 600 | 0.16 | 0.006 | 0.3
5822479 | 지상 5층 | 지상 5층 | 5822266 | 1100 | 0.285 | 0.011 | 0.56
5822484 | 지상 5층 | 지상 5층 | 5822266 | 743.357 | 0.195839 | 0.00743357 | 0.381679
5822485 | 지상 5층 | 지상 5층 | 5822266 | 743.357 | 0.195839 | 0.00743357 | 0.381679
5822486 | 지상 5층 | 지상 5층 | 5822266 | 718.357 | 0.189589 | 0.00718357 | 0.379179
5822487 | 지상 5층 | 지상 5층 | 5822266 | 718.357 | 0.189589 | 0.00718357 | 0.379179
5822488 | 지상 5층 | 지상 5층 | 5822266 | 300 | 0.085 | 0.003 | 0.16
5822489 | 지상 5층 | 지상 5층 | 5822266 | 600 | 0.16 | 0.006 | 0.3
5822490 | 지상 5층 | 지상 5층 | 5822266 | 1100 | 0.285 | 0.011 | 0.56
5822495 | 지상 5층 | 지상 5층 | 5822266 | 743.357 | 0.195839 | 0.00743357 | 0.381679
5822496 | 지상 5층 | 지상 5층 | 5822266 | 743.357 | 0.195839 | 0.00743357 | 0.381679
5822497 | 지상 5층 | 지상 5층 | 5822266 | 718.357 | 0.189589 | 0.00718357 | 0.379179
5822498 | 지상 5층 | 지상 5층 | 5822266 | 718.357 | 0.189589 | 0.00718357 | 0.379179
5822499 | 지상 5층 | 지상 5층 | 5822266 | 300 | 0.085 | 0.003 | 0.16
5822500 | 지상 5층 | 지상 5층 | 5822266 | 600 | 0.16 | 0.006 | 0.3
5822501 | 지상 5층 | 지상 5층 | 5822266 | 1100 | 0.285 | 0.011 | 0.56
5822506 | 지상 5층 | 지상 5층 | 5822266 | 743.357 | 0.195839 | 0.00743357 | 0.381679
5822507 | 지상 5층 | 지상 5층 | 5822266 | 743.357 | 0.195839 | 0.00743357 | 0.381679
5822508 | 지상 5층 | 지상 5층 | 5822266 | 718.357 | 0.189589 | 0.00718357 | 0.379179
5822509 | 지상 5층 | 지상 5층 | 5822266 | 718.357 | 0.189589 | 0.00718357 | 0.379179
5822510 | 지상 5층 | 지상 5층 | 5822266 | 300 | 0.085 | 0.003 | 0.16
5822511 | 지상 5층 | 지상 5층 | 5822266 | 600 | 0.16 | 0.006 | 0.3
5822512 | 지상 5층 | 지상 5층 | 5822266 | 1100 | 0.285 | 0.011 | 0.56
5822517 | 지상 5층 | 지상 5층 | 5822266 | 743.357 | 0.195839 | 0.00743357 | 0.381679
5822518 | 지상 5층 | 지상 5층 | 5822266 | 743.357 | 0.195839 | 0.00743357 | 0.381679
5822519 | 지상 5층 | 지상 5층 | 5822266 | 718.357 | 0.189589 | 0.00718357 | 0.379179
5822520 | 지상 5층 | 지상 5층 | 5822266 | 718.357 | 0.189589 | 0.00718357 | 0.379179
5822521 | 지상 5층 | 지상 5층 | 5822266 | 300 | 0.085 | 0.003 | 0.16
5822522 | 지상 5층 | 지상 5층 | 5822266 | 600 | 0.16 | 0.006 | 0.3
5822523 | 지상 5층 | 지상 5층 | 5822266 | 1100 | 0.285 | 0.011 | 0.56
5822528 | 지상 5층 | 지상 5층 | 5822266 | 743.357 | 0.195839 | 0.00743357 | 0.381679
5822529 | 지상 5층 | 지상 5층 | 5822266 | 912.5 | 0.238125 | 0.009125 | 0.47625
5822530 | 지상 5층 | 지상 5층 | 5822266 | 912.5 | 0.238125 | 0.009125 | 0.47625
5822531 | 지상 5층 | 지상 5층 | 5822266 | 912.5 | 0.238125 | 0.009125 | 0.47625
5822532 | 지상 5층 | 지상 5층 | 5822266 | 300 | 0.085 | 0.003 | 0.16
5822533 | 지상 5층 | 지상 5층 | 5822266 | 600 | 0.16 | 0.006 | 0.3
5822534 | 지상 5층 | 지상 5층 | 5822266 | 1100 | 0.285 | 0.011 | 0.56
5822539 | 지상 5층 | 지상 5층 | 5822266 | 828.5 | 0.217125 | 0.008285 | 0.42425
5822540 | 지상 5층 | 지상 5층 | 5822266 | 828.5 | 0.217125 | 0.008285 | 0.42425
5822541 | 지상 5층 | 지상 5층 | 5822266 | 803.5 | 0.210875 | 0.008035 | 0.42175
5822542 | 지상 5층 | 지상 5층 | 5822266 | 803.5 | 0.210875 | 0.008035 | 0.42175
5822543 | 지상 5층 | 지상 5층 | 5822266 | 650 | 0.1725 | 0.0065 | 0.345
5822548 | 지상 5층 | 지상 5층 | 5822266 | 828.5 | 0.217125 | 0.008285 | 0.42425
5822549 | 지상 5층 | 지상 5층 | 5822266 | 828.5 | 0.217125 | 0.008285 | 0.42425
5822550 | 지상 5층 | 지상 5층 | 5822266 | 803.5 | 0.210875 | 0.008035 | 0.42175
5822551 | 지상 5층 | 지상 5층 | 5822266 | 803.5 | 0.210875 | 0.008035 | 0.42175
5822552 | 지상 5층 | 지상 5층 | 5822266 | 650 | 0.1725 | 0.0065 | 0.345
5822557 | 지상 5층 | 지상 5층 | 5822266 | 828.5 | 0.217125 | 0.008285 | 0.42425
5822558 | 지상 5층 | 지상 5층 | 5822266 | 828.5 | 0.217125 | 0.008285 | 0.42425
5822559 | 지상 5층 | 지상 5층 | 5822266 | 803.5 | 0.210875 | 0.008035 | 0.42175
5822560 | 지상 5층 | 지상 5층 | 5822266 | 803.5 | 0.210875 | 0.008035 | 0.42175
5822561 | 지상 5층 | 지상 5층 | 5822266 | 650 | 0.1725 | 0.0065 | 0.345
5822566 | 지상 5층 | 지상 5층 | 5822266 | 828.5 | 0.217125 | 0.008285 | 0.42425
5822567 | 지상 5층 | 지상 5층 | 5822266 | 828.5 | 0.217125 | 0.008285 | 0.42425
5822568 | 지상 5층 | 지상 5층 | 5822266 | 803.5 | 0.210875 | 0.008035 | 0.42175
5822569 | 지상 5층 | 지상 5층 | 5822266 | 803.5 | 0.210875 | 0.008035 | 0.42175
5822570 | 지상 5층 | 지상 5층 | 5822266 | 650 | 0.1725 | 0.0065 | 0.345
5822575 | 지상 5층 | 지상 5층 | 5822266 | 754 | 0.1985 | 0.00754 | 0.387
5822576 | 지상 5층 | 지상 5층 | 5822266 | 754 | 0.1985 | 0.00754 | 0.387
5822577 | 지상 5층 | 지상 5층 | 5822266 | 729 | 0.19225 | 0.00729 | 0.3845
5822578 | 지상 5층 | 지상 5층 | 5822266 | 729 | 0.19225 | 0.00729 | 0.3845
5822579 | 지상 5층 | 지상 5층 | 5822266 | 650 | 0.1725 | 0.0065 | 0.345
5822584 | 지상 5층 | 지상 5층 | 5822266 | 754 | 0.1985 | 0.00754 | 0.387
5822585 | 지상 5층 | 지상 5층 | 5822266 | 754 | 0.1985 | 0.00754 | 0.387
5822586 | 지상 5층 | 지상 5층 | 5822266 | 729 | 0.19225 | 0.00729 | 0.3845
5822587 | 지상 5층 | 지상 5층 | 5822266 | 729 | 0.19225 | 0.00729 | 0.3845
5822588 | 지상 5층 | 지상 5층 | 5822266 | 650 | 0.1725 | 0.0065 | 0.345
5822593 | 지상 5층 | 지상 5층 | 5822266 | 754 | 0.1985 | 0.00754 | 0.387
5822594 | 지상 5층 | 지상 5층 | 5822266 | 754 | 0.1985 | 0.00754 | 0.387
5822595 | 지상 5층 | 지상 5층 | 5822266 | 729 | 0.19225 | 0.00729 | 0.3845
5822596 | 지상 5층 | 지상 5층 | 5822266 | 729 | 0.19225 | 0.00729 | 0.3845
5822597 | 지상 5층 | 지상 5층 | 5822266 | 650 | 0.1725 | 0.0065 | 0.345
5822602 | 지상 5층 | 지상 5층 | 5822266 | 754 | 0.1985 | 0.00754 | 0.387
5822603 | 지상 5층 | 지상 5층 | 5822266 | 754 | 0.1985 | 0.00754 | 0.387
5822604 | 지상 5층 | 지상 5층 | 5822266 | 729 | 0.19225 | 0.00729 | 0.3845
5822605 | 지상 5층 | 지상 5층 | 5822266 | 729 | 0.19225 | 0.00729 | 0.3845
5822606 | 지상 5층 | 지상 5층 | 5822266 | 650 | 0.1725 | 0.0065 | 0.345
5822611 | 지상 5층 | 지상 5층 | 5822266 | 741.5 | 0.195375 | 0.007415 | 0.38075
5822612 | 지상 5층 | 지상 5층 | 5822266 | 741.5 | 0.195375 | 0.007415 | 0.38075
5822613 | 지상 5층 | 지상 5층 | 5822266 | 716.5 | 0.189125 | 0.007165 | 0.37825
5822614 | 지상 5층 | 지상 5층 | 5822266 | 716.5 | 0.189125 | 0.007165 | 0.37825
5822615 | 지상 5층 | 지상 5층 | 5822266 | 650 | 0.1725 | 0.0065 | 0.345
5822620 | 지상 5층 | 지상 5층 | 5822266 | 741.5 | 0.195375 | 0.007415 | 0.38075
5822621 | 지상 5층 | 지상 5층 | 5822266 | 741.5 | 0.195375 | 0.007415 | 0.38075
5822622 | 지상 5층 | 지상 5층 | 5822266 | 716.5 | 0.189125 | 0.007165 | 0.37825
5822623 | 지상 5층 | 지상 5층 | 5822266 | 716.5 | 0.189125 | 0.007165 | 0.37825
5822624 | 지상 5층 | 지상 5층 | 5822266 | 650 | 0.1725 | 0.0065 | 0.345
5822629 | 지상 5층 | 지상 5층 | 5822266 | 741.5 | 0.195375 | 0.007415 | 0.38075
5822630 | 지상 5층 | 지상 5층 | 5822266 | 741.5 | 0.195375 | 0.007415 | 0.38075
5822631 | 지상 5층 | 지상 5층 | 5822266 | 716.5 | 0.189125 | 0.007165 | 0.37825
5822632 | 지상 5층 | 지상 5층 | 5822266 | 716.5 | 0.189125 | 0.007165 | 0.37825
5822633 | 지상 5층 | 지상 5층 | 5822266 | 650 | 0.1725 | 0.0065 | 0.345
5822638 | 지상 5층 | 지상 5층 | 5822266 | 741.5 | 0.195375 | 0.007415 | 0.38075
5822639 | 지상 5층 | 지상 5층 | 5822266 | 741.5 | 0.195375 | 0.007415 | 0.38075
5822640 | 지상 5층 | 지상 5층 | 5822266 | 716.5 | 0.189125 | 0.007165 | 0.37825
5822641 | 지상 5층 | 지상 5층 | 5822266 | 716.5 | 0.189125 | 0.007165 | 0.37825
5822642 | 지상 5층 | 지상 5층 | 5822266 | 650 | 0.1725 | 0.0065 | 0.345
5822647 | 지상 5층 | 지상 5층 | 5822266 | 743.357 | 0.195839 | 0.00743357 | 0.381679
5822648 | 지상 5층 | 지상 5층 | 5822266 | 743.357 | 0.195839 | 0.00743357 | 0.381679
5822649 | 지상 5층 | 지상 5층 | 5822266 | 718.357 | 0.189589 | 0.00718357 | 0.379179
5822650 | 지상 5층 | 지상 5층 | 5822266 | 718.357 | 0.189589 | 0.00718357 | 0.379179
5822651 | 지상 5층 | 지상 5층 | 5822266 | 650 | 0.1725 | 0.0065 | 0.345
5822656 | 지상 5층 | 지상 5층 | 5822266 | 743.357 | 0.195839 | 0.00743357 | 0.381679
5822657 | 지상 5층 | 지상 5층 | 5822266 | 743.357 | 0.195839 | 0.00743357 | 0.381679
5822658 | 지상 5층 | 지상 5층 | 5822266 | 718.357 | 0.189589 | 0.00718357 | 0.379179
5822659 | 지상 5층 | 지상 5층 | 5822266 | 718.357 | 0.189589 | 0.00718357 | 0.379179
5822660 | 지상 5층 | 지상 5층 | 5822266 | 650 | 0.1725 | 0.0065 | 0.345
5822665 | 지상 5층 | 지상 5층 | 5822266 | 743.357 | 0.195839 | 0.00743357 | 0.381679
5822666 | 지상 5층 | 지상 5층 | 5822266 | 743.357 | 0.195839 | 0.00743357 | 0.381679
5822667 | 지상 5층 | 지상 5층 | 5822266 | 718.357 | 0.189589 | 0.00718357 | 0.379179
5822668 | 지상 5층 | 지상 5층 | 5822266 | 718.357 | 0.189589 | 0.00718357 | 0.379179
5822669 | 지상 5층 | 지상 5층 | 5822266 | 650 | 0.1725 | 0.0065 | 0.345
5822674 | 지상 5층 | 지상 5층 | 5822266 | 743.357 | 0.195839 | 0.00743357 | 0.381679
5822675 | 지상 5층 | 지상 5층 | 5822266 | 743.357 | 0.195839 | 0.00743357 | 0.381679
5822676 | 지상 5층 | 지상 5층 | 5822266 | 718.357 | 0.189589 | 0.00718357 | 0.379179
5822677 | 지상 5층 | 지상 5층 | 5822266 | 718.357 | 0.189589 | 0.00718357 | 0.379179
5822678 | 지상 5층 | 지상 5층 | 5822266 | 650 | 0.1725 | 0.0065 | 0.345
5822683 | 지상 5층 | 지상 5층 | 5822266 | 743.357 | 0.195839 | 0.00743357 | 0.381679
5822684 | 지상 5층 | 지상 5층 | 5822266 | 743.357 | 0.195839 | 0.00743357 | 0.381679
5822685 | 지상 5층 | 지상 5층 | 5822266 | 718.357 | 0.189589 | 0.00718357 | 0.379179
5822686 | 지상 5층 | 지상 5층 | 5822266 | 718.357 | 0.189589 | 0.00718357 | 0.379179
5822687 | 지상 5층 | 지상 5층 | 5822266 | 650 | 0.1725 | 0.0065 | 0.345
5822692 | 지상 5층 | 지상 5층 | 5822266 | 743.357 | 0.195839 | 0.00743357 | 0.381679
5822693 | 지상 5층 | 지상 5층 | 5822266 | 743.357 | 0.195839 | 0.00743357 | 0.381679
5822694 | 지상 5층 | 지상 5층 | 5822266 | 718.357 | 0.189589 | 0.00718357 | 0.379179
5822695 | 지상 5층 | 지상 5층 | 5822266 | 718.357 | 0.189589 | 0.00718357 | 0.379179
5822696 | 지상 5층 | 지상 5층 | 5822266 | 650 | 0.1725 | 0.0065 | 0.345
5822701 | 지상 5층 | 지상 5층 | 5822266 | 743.357 | 0.195839 | 0.00743357 | 0.381679
5822702 | 지상 5층 | 지상 5층 | 5822266 | 743.357 | 0.195839 | 0.00743357 | 0.381679
5822703 | 지상 5층 | 지상 5층 | 5822266 | 718.357 | 0.189589 | 0.00718357 | 0.379179
5822704 | 지상 5층 | 지상 5층 | 5822266 | 718.357 | 0.189589 | 0.00718357 | 0.379179
5822705 | 지상 5층 | 지상 5층 | 5822266 | 650 | 0.1725 | 0.0065 | 0.345
5909174 | 지상 2층 | 지상 2층 | 5909172 | 520 | 0.14 | 0.0052 | 0.28
5909175 | 지상 2층 | 지상 2층 | 5909172 | 525 | 0.14125 | 0.00525 | 0.2825
5909176 | 지상 2층 | 지상 2층 | 5909172 | 2100 | 0.535 | 0.021 | 1.06
5909177 | 지상 2층 | 지상 2층 | 5909172 | 920 | 0.24 | 0.0092 | 0.47
5909180 | 지상 2층 | 지상 2층 | 5909172 | 920 | 0.24 | 0.0092 | 0.47
5909181 | 지상 2층 | 지상 2층 | 5909172 | 2100 | 0.535 | 0.021 | 1.06
5909182 | 지상 2층 | 지상 2층 | 5909172 | 525 | 0.14125 | 0.00525 | 0.2825
5909186 | 지상 2층 | 지상 2층 | 5909172 | 525 | 0.14125 | 0.00525 | 0.2825
5909188 | 지상 2층 | 지상 2층 | 5909172 | 1505 | 0.38625 | 0.01505 | 0.7725
5909189 | 지상 2층 | 지상 2층 | 5909172 | 2100 | 0.535 | 0.021 | 1.06
5909190 | 지상 2층 | 지상 2층 | 5909172 | 920 | 0.24 | 0.0092 | 0.47
5909194 | 지상 2층 | 지상 2층 | 5909172 | 1505 | 0.38625 | 0.01505 | 0.7725
5909195 | 지상 2층 | 지상 2층 | 5909172 | 520 | 0.14 | 0.0052 | 0.28
5909196 | 지상 2층 | 지상 2층 | 5909172 | 520 | 0.14 | 0.0052 | 0.28
5909197 | 지상 2층 | 지상 2층 | 5909172 | 2100 | 0.535 | 0.021 | 1.06
5909198 | 지상 2층 | 지상 2층 | 5909172 | 920 | 0.24 | 0.0092 | 0.47
5909204 | 지상 9층 | 지상 9층 | 5909202 | 525 | 0.14125 | 0.00525 | 0.2825
5909206 | 지상 9층 | 지상 9층 | 5909202 | 2100 | 0.535 | 0.021 | 1.06
5909207 | 지상 9층 | 지상 9층 | 5909202 | 920 | 0.24 | 0.0092 | 0.47
5909210 | 지상 9층 | 지상 9층 | 5909202 | 920 | 0.24 | 0.0092 | 0.47
5909211 | 지상 9층 | 지상 9층 | 5909202 | 2100 | 0.535 | 0.021 | 1.06
5909212 | 지상 9층 | 지상 9층 | 5909202 | 525 | 0.14125 | 0.00525 | 0.2825
5909216 | 지상 9층 | 지상 9층 | 5909202 | 525 | 0.14125 | 0.00525 | 0.2825
5909218 | 지상 9층 | 지상 9층 | 5909202 | 1500 | 0.385 | 0.015 | 0.77
5909219 | 지상 9층 | 지상 9층 | 5909202 | 2100 | 0.535 | 0.021 | 1.06
5909220 | 지상 9층 | 지상 9층 | 5909202 | 920 | 0.24 | 0.0092 | 0.47
5909224 | 지상 9층 | 지상 9층 | 5909202 | 1500 | 0.385 | 0.015 | 0.77
5909226 | 지상 9층 | 지상 9층 | 5909202 | 525 | 0.14125 | 0.00525 | 0.2825
5909227 | 지상 9층 | 지상 9층 | 5909202 | 2100 | 0.535 | 0.021 | 1.06
5909228 | 지상 9층 | 지상 9층 | 5909202 | 920 | 0.24 | 0.0092 | 0.47
5909234 | 지상 10층 | 지상 10층 | 5909232 | 507.025 | 0.136756 | 0.00507025 | 0.273513
5909236 | 지상 10층 | 지상 10층 | 5909232 | 2100 | 0.535 | 0.021 | 1.06
5909237 | 지상 10층 | 지상 10층 | 5909232 | 1420 | 0.365 | 0.0142 | 0.72
5909240 | 지상 10층 | 지상 10층 | 5909232 | 1420 | 0.365 | 0.0142 | 0.72
5909241 | 지상 10층 | 지상 10층 | 5909232 | 2100 | 0.535 | 0.021 | 1.06
5909242 | 지상 10층 | 지상 10층 | 5909232 | 525 | 0.14125 | 0.00525 | 0.2825
5909246 | 지상 10층 | 지상 10층 | 5909232 | 525 | 0.14125 | 0.00525 | 0.2825
5909248 | 지상 10층 | 지상 10층 | 5909232 | 1500 | 0.385 | 0.015 | 0.77
5909249 | 지상 10층 | 지상 10층 | 5909232 | 2100 | 0.535 | 0.021 | 1.06
5909250 | 지상 10층 | 지상 10층 | 5909232 | 1420 | 0.365 | 0.0142 | 0.72
5909254 | 지상 10층 | 지상 10층 | 5909232 | 1500 | 0.385 | 0.015 | 0.77
5909256 | 지상 10층 | 지상 10층 | 5909232 | 507.025 | 0.136756 | 0.00507025 | 0.273513
5909257 | 지상 10층 | 지상 10층 | 5909232 | 2100 | 0.535 | 0.021 | 1.06
5909258 | 지상 10층 | 지상 10층 | 5909232 | 1420 | 0.365 | 0.0142 | 0.72
7697252 | 지상 3층 | 지상 3층 | 7697250 | 280.009 | 0.0800022 | 0.00280009 | 0.160004
7697253 | 지상 3층 | 지상 3층 | 7697250 | 2100 | 0.535 | 0.021 | 1.06
7697257 | 지상 3층 | 지상 3층 | 7697250 | 520 | 0.14 | 0.0052 | 0.27
7697259 | 지상 3층 | 지상 3층 | 7697250 | 814.991 | 0.213748 | 0.00814991 | 0.427496
7697263 | 지상 3층 | 지상 3층 | 7697250 | 814.991 | 0.213748 | 0.00814991 | 0.427496
7697264 | 지상 3층 | 지상 3층 | 7697250 | 1495 | 0.38375 | 0.01495 | 0.7675
7697265 | 지상 3층 | 지상 3층 | 7697250 | 2100 | 0.535 | 0.021 | 1.06
7697266 | 지상 3층 | 지상 3층 | 7697250 | 520 | 0.14 | 0.0052 | 0.27
7697272 | 지상 3층 | 지상 3층 | 7697250 | 1495 | 0.38375 | 0.01495 | 0.7675
7697273 | 지상 3층 | 지상 3층 | 7697250 | 280.009 | 0.0800022 | 0.00280009 | 0.160004

# IfcMember: 직사각형 멀리언:CW200-직사각형 멀리언 60 x 100mm (19)
Type - PredefinedType: MULLION; Material: <Unnamed>
Type - ID 데이터 - 유형 이름: CW200-직사각형 멀리언 60 x 100mm
Type - 구속조건 - 각도: 0 deg; 간격띄우기: 0 mm
Type - 기타 - 카테고리: 커튼월 멀리언; KBIMS-부위코드: E336; 조달청표준공사코드: ALC1; 패밀리 이름: 직사각형 멀리언
Type - 시공 - 위치: 면과 직각; 코너 멀리언: no; 프로파일: 시스템 멀리언 프로파일: 직사각형; 두께: 100 mm
Type - 치수 - 사이드 1의 폭: 30 mm; 사이드 2의 폭: 30 mm
Type - Pset_MemberCommon - IsExternal: no
공정 - 생성 공정: 새 구성
기타 - 패밀리: 직사각형 멀리언; 유형: CW200-직사각형 멀리언 60 x 100mm; 유형 ID: 2126803; 패밀리 및 유형: 직사각형 멀리언: CW200-직사각형 멀리언 60 x 100mm
Pset_MemberCommon - Reference: CW200-직사각형 멀리언 60 x 100mm
Pset_QuantityTakeOff - Reference: CW200-직사각형 멀리언 60 x 100mm
Name (직사각형 멀리언:CW200-직사각형 멀리언 60 x 100mm:...) | In | 레벨 | 호스트 ID | 길이 (mm) = Span (mm) | 면적 (m2) = CrossSectionArea (m2) | 체적 (m3) = NetVolume (m3) | NetSurfaceArea (m2)
2851167 | 지상 1층 | 지상 1층 | 2850019 | 1945 | 0.3172 | 0.01167 | 0.6344
7694629 | 지상 2층 | 지상 2층 | 2923615 | 920 | 0.1532 | 0.00552 | 0.3004
7694630 | 지상 2층 | 지상 2층 | 2923615 | 2100 | 0.342 | 0.0126 | 0.678
7697180 | 지상 9층 | 지상 9층 | 5393189 | 920 | 0.1532 | 0.00552 | 0.3004
7697181 | 지상 9층 | 지상 9층 | 5393189 | 2100 | 0.342 | 0.0126 | 0.678
7697156 | 지상 4층 | 지상 4층 | 5403580 | 520 | 0.0892 | 0.00312 | 0.1724
7697157 | 지상 4층 | 지상 4층 | 5403580 | 2100 | 0.342 | 0.0126 | 0.678
7697168 | 지상 5층 | 지상 5층 | 5403601 | 520 | 0.0892 | 0.00312 | 0.1724
7697169 | 지상 5층 | 지상 5층 | 5403601 | 2100 | 0.342 | 0.0126 | 0.678
7697171 | 지상 6층 | 지상 6층 | 5403620 | 520 | 0.0892 | 0.00312 | 0.1724
7697172 | 지상 6층 | 지상 6층 | 5403620 | 2100 | 0.342 | 0.0126 | 0.678
7697174 | 지상 7층 | 지상 7층 | 5403639 | 520 | 0.0892 | 0.00312 | 0.1724
7697175 | 지상 7층 | 지상 7층 | 5403639 | 2100 | 0.342 | 0.0126 | 0.678
7697177 | 지상 8층 | 지상 8층 | 5403658 | 520 | 0.0892 | 0.00312 | 0.1724
7697178 | 지상 8층 | 지상 8층 | 5403658 | 2100 | 0.342 | 0.0126 | 0.678
7697185 | 지상 10층 | 지상 10층 | 5403726 | 1420 | 0.2332 | 0.00852 | 0.4604
7697186 | 지상 10층 | 지상 10층 | 5403726 | 2100 | 0.342 | 0.0126 | 0.678
7697274 | 지상 3층 | 지상 3층 | 7697250 | 520 | 0.0892 | 0.00312 | 0.1724
7697275 | 지상 3층 | 지상 3층 | 7697250 | 2100 | 0.342 | 0.0126 | 0.678

# IfcOpeningElement: Opening (863)
Name | In | Depth (mm) | Height (mm) | Width (mm) | 생성 공정 | 카테고리 | 유형 | 유형 ID | 패밀리 | 패밀리 및 유형 | 면적 (m2) | Reference | Pset_OpeningElementCommon, sets with these values
기본 벽:WA111-철근콘크리트구조 벽 200mm_W1:2818398 | 지상 1층 | 504.8 | 1200 | 3520 | 새 구성 | 벽 | CW112-스테인리스 스틸 커튼월 | 7675291 | 커튼월 | 커튼월: CW112-스테인리스 스틸 커튼월 | 4.224 | CW112-스테인리스 스틸 커튼월 | 2 | ID 데이터 - 마크: 14; 해설: SSD; 구속조건 - 매스와 관련됨: no; 룸 경계: yes; 벽 베이스가 부착됩니다.: no; 상단이 부착됩니다.: no; 베이스 구속조건: 지상 1층; 상단 구속조건: 상위 레벨: 지상 2층; 미연결 높이: 3520 mm; 베이스 간격띄우기: 80 mm; 상단 간격띄우기: -1200 mm; 구조 - 구조: no; 구조적 용도: 비교좌장치; 단면형상 정의 - 단면형상: 수직; 수직 그리드 - 각도: 0 deg; 간격띄우기: 0 mm; 맞춤: 시작; 번호: 4; sets with these values: 2; 치수 - 길이: 1200 mm
기본 벽:WA111-철근콘크리트구조 벽 200mm_W1:2819622 | 지상 1층 | 504.8 | 3380 | 7487.49 | 새 구성 | 벽 | CW112-스테인리스 스틸 커튼월 | 7675291 | 커튼월 | 커튼월: CW112-스테인리스 스틸 커튼월 | 25.3077 | CW112-스테인리스 스틸 커튼월 | 2 | ID 데이터 - 마크: 19; 해설: SSD; 구속조건 - 매스와 관련됨: no; 룸 경계: yes; 벽 베이스가 부착됩니다.: no; 상단이 부착됩니다.: no; 베이스 구속조건: 지상 1층; 상단 구속조건: 상위 레벨: 지상 2층; 미연결 높이: 4800 mm; 베이스 간격띄우기: 0 mm; 상단 간격띄우기: 0 mm; 구조 - 구조: no; 구조적 용도: 비교좌장치; 단면형상 정의 - 단면형상: 수직; 수직 그리드 - 각도: 0 deg; 간격띄우기: 0 mm; 맞춤: 시작; 번호: 4; sets with these values: 2; 치수 - 길이: 7487.49 mm
기본 벽:WA111-철근콘크리트구조 벽 200mm_CW1:2820022 | 지상 2층 | 3048 | 1000 | 1600 | 새 구성 | 창 | WD812-미들창(스테인리스 스틸) 하부개폐 1000x1600mm | 7464744 | WD812-미들창(스테인리스 스틸) | WD812-미들창(스테인리스 스틸): WD812-미들창(스테인리스 스틸) 하부개폐 1000x1600mm | 2.46752 | WD812-미들창(스테인리스 스틸) 하부개폐 1000x1600mm | 2 | 구속조건 - 레벨: 지상 1층; 씰 높이: 3600 mm; 기타 - 창의개폐비: 50; 헤드 높이: 5200 mm; 호스트 ID: 2818037; 치수 - 벽체 opening 면적: 1.6 m2; 체적: 0.0593112 m3
기본 벽:WA111-철근콘크리트구조 벽 200mm_CW1:2820028:1 | 지상 2층 |  |  |  |  |  |  |  |  |  |  | WA111-철근콘크리트구조 벽 200mm_CW1 | 2
기본 벽:WA111-철근콘크리트구조 벽 200mm_W1:2820046 | 지상 2층 | 504.8 | 1200 | 3120 | 새 구성 | 벽 | CW112-스테인리스 스틸 커튼월 | 7675291 | 커튼월 | 커튼월: CW112-스테인리스 스틸 커튼월 | 3.744 | CW112-스테인리스 스틸 커튼월 | 2 | ID 데이터 - 마크: 0; 해설: AW; 구속조건 - 매스와 관련됨: no; 룸 경계: yes; 벽 베이스가 부착됩니다.: no; 상단이 부착됩니다.: no; 베이스 구속조건: 지상 2층; 상단 구속조건: 상위 레벨: 지상 3층; 미연결 높이: 3120 mm; 베이스 간격띄우기: 80 mm; 상단 간격띄우기: -1300 mm; 구조 - 구조: no; 구조적 용도: 비교좌장치; 단면형상 정의 - 단면형상: 수직; 수직 그리드 - 각도: 0 deg; 간격띄우기: 0 mm; 맞춤: 시작; 번호: 4; sets with these values: 2; 치수 - 길이: 1200 mm
기본 벽:WA111-철근콘크리트구조 벽 200mm_CW1:2820050 | 지상 2층 | 504.8 | 3020 | 2818.01 | 새 구성 | 벽 | CW112-스테인리스 스틸 커튼월 | 7675291 | 커튼월 | 커튼월: CW112-스테인리스 스틸 커튼월 | 8.51039 | CW112-스테인리스 스틸 커튼월 | 2 | ID 데이터 - 마크: 29; 해설: SSD; 구속조건 - 매스와 관련됨: no; 룸 경계: yes; 벽 베이스가 부착됩니다.: no; 상단이 부착됩니다.: no; 베이스 구속조건: 지상 2층; 상단 구속조건: 상위 레벨: 지상 3층; 미연결 높이: 3020 mm; 베이스 간격띄우기: 80 mm; 상단 간격띄우기: -1400 mm; 구조 - 구조: no; 구조적 용도: 비교좌장치; 단면형상 정의 - 단면형상: 수직; 수직 그리드 - 각도: 0 deg; 간격띄우기: 0 mm; 맞춤: 시작; 번호: 4; sets with these values: 2; 치수 - 길이: 2818.01 mm
기본 벽:WA111-철근콘크리트구조 벽 200mm_CW1:2820062 | 지상 2층 | 504.8 | 1300.01 | 2020 | 새 구성 | 벽 | CW112-스테인리스 스틸 커튼월 | 7675291 | 커튼월 | 커튼월: CW112-스테인리스 스틸 커튼월 | 2.62602 | CW112-스테인리스 스틸 커튼월 | 2 | ID 데이터 - 마크: 13; 해설: SSD; 구속조건 - 매스와 관련됨: no; 룸 경계: yes; 벽 베이스가 부착됩니다.: no; 상단이 부착됩니다.: no; 베이스 구속조건: 지상 2층; 상단 구속조건: 상위 레벨: 지상 3층; 미연결 높이: 2020 mm; 베이스 간격띄우기: 80 mm; 상단 간격띄우기: -2400 mm; 구조 - 구조: no; 구조적 용도: 비교좌장치; 단면형상 정의 - 단면형상: 수직; 수직 그리드 - 각도: 0 deg; 간격띄우기: 0 mm; 맞춤: 시작; 번호: 4; sets with these values: 2; 치수 - 길이: 1300.01 mm
기본 벽:WA111-철근콘크리트구조 벽 200mm_CW1:2820066 | 지상 2층 | 504.8 | 3120 | 8970.43 | 새 구성 | 벽 | CW112-스테인리스 스틸 커튼월 | 7675291 | 커튼월 | 커튼월: CW112-스테인리스 스틸 커튼월 | 27.9878 | CW112-스테인리스 스틸 커튼월 | 2 | ID 데이터 - 마크: 21; 해설: AW; 구속조건 - 매스와 관련됨: no; 룸 경계: yes; 벽 베이스가 부착됩니다.: no; 상단이 부착됩니다.: no; 베이스 구속조건: 지상 2층; 상단 구속조건: 상위 레벨: 지상 3층; 미연결 높이: 3120 mm; 베이스 간격띄우기: 80 mm; 상단 간격띄우기: -1300 mm; 구조 - 구조: no; 구조적 용도: 비교좌장치; 단면형상 정의 - 단면형상: 수직; 수직 그리드 - 각도: 0 deg; 간격띄우기: 0 mm; 맞춤: 시작; 번호: 4; sets with these values: 2; 치수 - 길이: 8970.43 mm
기본 벽:WA111-철근콘크리트구조 벽 200mm_CW1:2820447:1 | 지상 3층 |  |  |  |  |  |  |  |  |  |  | WA111-철근콘크리트구조 벽 200mm_CW1 | 2
기본 벽:WA111-철근콘크리트구조 벽 200mm_W1:2820463 | 지상 3층 | 504.8 | 2099.37 | 2620 | 새 구성 | 벽 | CW112-스테인리스 스틸 커튼월 | 7675291 | 커튼월 | 커튼월: CW112-스테인리스 스틸 커튼월 | 5.50034 | CW112-스테인리스 스틸 커튼월 | 2 | ID 데이터 - 마크: 22; 해설: AW; 구속조건 - 매스와 관련됨: no; 룸 경계: yes; 벽 베이스가 부착됩니다.: no; 상단이 부착됩니다.: no; 베이스 구속조건: 지상 3층; 상단 구속조건: 상위 레벨: 지상 4층; 미연결 높이: 2620 mm; 베이스 간격띄우기: 80 mm; 상단 간격띄우기: -1400 mm; 구조 - 구조: no; 구조적 용도: 비교좌장치; 단면형상 정의 - 단면형상: 수직; 수직 그리드 - 각도: 0 deg; 간격띄우기: 0 mm; 맞춤: 시작; 번호: 4; sets with these values: 2; 치수 - 길이: 2099.37 mm
기본 벽:WA111-철근콘크리트구조 벽 200mm_CW1:2820477:1 | 지상 3층 |  |  |  |  |  |  |  |  |  |  | WA111-철근콘크리트구조 벽 200mm_CW1 | 2
기본 벽:WA111-철근콘크리트구조 벽 200mm_CW1:2820479 | 지상 3층 | 504.8 | 1250 | 2020 | 새 구성 | 벽 | CW112-스테인리스 스틸 커튼월 | 7675291 | 커튼월 | 커튼월: CW112-스테인리스 스틸 커튼월 | 2.525 | CW112-스테인리스 스틸 커튼월 | 2 | ID 데이터 - 마크: 13; 해설: SSD; 구속조건 - 매스와 관련됨: no; 룸 경계: yes; 벽 베이스가 부착됩니다.: no; 상단이 부착됩니다.: no; 베이스 구속조건: 지상 3층; 상단 구속조건: 상위 레벨: 지상 4층; 미연결 높이: 2020 mm; 베이스 간격띄우기: 80 mm; 상단 간격띄우기: -2000 mm; 구조 - 구조: no; 구조적 용도: 비교좌장치; 단면형상 정의 - 단면형상: 수직; 수직 그리드 - 각도: 0 deg; 간격띄우기: 0 mm; 맞춤: 시작; 번호: 4; sets with these values: 2; 치수 - 길이: 1250 mm
기본 벽:WA111-철근콘크리트구조 벽 200mm_W1:2820483 | 지상 3층 | 504.8 | 2620 | 8991.01 | 새 구성 | 벽 | CW112-스테인리스 스틸 커튼월 | 7675291 | 커튼월 | 커튼월: CW112-스테인리스 스틸 커튼월 | 23.5564 | CW112-스테인리스 스틸 커튼월 | 2 | ID 데이터 - 마크: 26; 해설: AW; 구속조건 - 매스와 관련됨: no; 룸 경계: yes; 벽 베이스가 부착됩니다.: no; 상단이 부착됩니다.: no; 베이스 구속조건: 지상 3층; 상단 구속조건: 상위 레벨: 지상 4층; 미연결 높이: 2620 mm; 베이스 간격띄우기: 80 mm; 상단 간격띄우기: -1400 mm; 구조 - 구조: no; 구조적 용도: 비교좌장치; 단면형상 정의 - 단면형상: 수직; 수직 그리드 - 각도: 0 deg; 간격띄우기: 0 mm; 맞춤: 시작; 번호: 4; sets with these values: 2; 치수 - 길이: 8991.01 mm
기본 벽:WA111-철근콘크리트구조 벽 200mm_CW1:2820691 | 지상 4층 | 3048 | 1000 | 1600 | 새 구성 | 창 | WD812-미들창(스테인리스 스틸) 하부개폐 1000x1600mm | 7464744 | WD812-미들창(스테인리스 스틸) | WD812-미들창(스테인리스 스틸): WD812-미들창(스테인리스 스틸) 하부개폐 1000x1600mm | 2.46752 | WD812-미들창(스테인리스 스틸) 하부개폐 1000x1600mm | 2 | 구속조건 - 레벨: 지상 3층; 씰 높이: 3030 mm; 기타 - 창의개폐비: 50; 헤드 높이: 4630 mm; 호스트 ID: 2820441; 치수 - 벽체 opening 면적: 1.6 m2; 체적: 0.0593112 m3
기본 벽:WA111-철근콘크리트구조 벽 200mm_CW1:2820729 | 지상 4층 | 504.8 |  |  | 새 구성 | 벽 | CW112-스테인리스 스틸 커튼월 | 7675291 | 커튼월 | 커튼월: CW112-스테인리스 스틸 커튼월 | 0.70275 | CW112-스테인리스 스틸 커튼월 | 2 | ID 데이터 - 마크: 13; 해설: SSD; 구속조건 - 매스와 관련됨: no; 룸 경계: yes; 벽 베이스가 부착됩니다.: no; 상단이 부착됩니다.: no; 베이스 구속조건: 지상 4층; 상단 구속조건: 상위 레벨: 지상 5층; 미연결 높이: 2020 mm; 베이스 간격띄우기: 80 mm; 상단 간격띄우기: -2000 mm; 구조 - 구조: no; 구조적 용도: 비교좌장치; 단면형상 정의 - 단면형상: 수직; 수직 그리드 - 각도: 0 deg; 간격띄우기: 0 mm; 맞춤: 시작; 번호: 4; sets with these values: 2; 치수 - 길이: 1250 mm; BaseQuantities - Area: 0.70275 m2
기본 벽:WA111-철근콘크리트구조 벽 200mm_CW1:2821193 | 지상 5층 | 3048 | 1000 | 1600 | 새 구성 | 창 | WD812-미들창(스테인리스 스틸) 하부개폐 1000x1600mm | 7464744 | WD812-미들창(스테인리스 스틸) | WD812-미들창(스테인리스 스틸): WD812-미들창(스테인리스 스틸) 하부개폐 1000x1600mm | 2.46752 | WD812-미들창(스테인리스 스틸) 하부개폐 1000x1600mm | 2 | 구속조건 - 레벨: 지상 4층; 씰 높이: 3030 mm; 기타 - 창의개폐비: 50; 헤드 높이: 4630 mm; 호스트 ID: 2820691; 치수 - 벽체 opening 면적: 1.6 m2; 체적: 0.0593112 m3
기본 벽:WA111-철근콘크리트구조 벽 200mm_CW1:2821231 | 지상 5층 | 504.8 |  |  | 새 구성 | 벽 | CW112-스테인리스 스틸 커튼월 | 7675291 | 커튼월 | 커튼월: CW112-스테인리스 스틸 커튼월 | 0.803768 | CW112-스테인리스 스틸 커튼월 | 2 | ID 데이터 - 마크: 13; 해설: SSD; 구속조건 - 매스와 관련됨: no; 룸 경계: yes; 벽 베이스가 부착됩니다.: no; 상단이 부착됩니다.: no; 베이스 구속조건: 지상 5층; 상단 구속조건: 상위 레벨: 지상 6층; 미연결 높이: 2020 mm; 베이스 간격띄우기: 80 mm; 상단 간격띄우기: -2000 mm; 구조 - 구조: no; 구조적 용도: 비교좌장치; 단면형상 정의 - 단면형상: 수직; 수직 그리드 - 각도: 0 deg; 간격띄우기: 0 mm; 맞춤: 시작; 번호: 4; sets with these values: 2; 치수 - 길이: 1300.01 mm; BaseQuantities - Area: 0.803768 m2
기본 벽:WA111-철근콘크리트구조 벽 200mm_CW1:2821453 | 지상 6층 | 3048 | 1000 | 1600 | 새 구성 | 창 | WD812-미들창(스테인리스 스틸) 하부개폐 1000x1600mm | 7464744 | WD812-미들창(스테인리스 스틸) | WD812-미들창(스테인리스 스틸): WD812-미들창(스테인리스 스틸) 하부개폐 1000x1600mm | 2.46752 | WD812-미들창(스테인리스 스틸) 하부개폐 1000x1600mm | 2 | 구속조건 - 레벨: 지상 5층; 씰 높이: 3030 mm; 기타 - 창의개폐비: 50; 헤드 높이: 4630 mm; 호스트 ID: 2821193; 치수 - 벽체 opening 면적: 1.6 m2; 체적: 0.0593112 m3
기본 벽:WA111-철근콘크리트구조 벽 200mm_CW1:2821489:1 | 지상 6층 |  |  |  |  |  |  |  |  |  |  | WA111-철근콘크리트구조 벽 200mm_CW1 | 2
기본 벽:WA111-철근콘크리트구조 벽 200mm_CW1:2821491 | 지상 6층 | 504.8 |  |  | 새 구성 | 벽 | CW112-스테인리스 스틸 커튼월 | 7675291 | 커튼월 | 커튼월: CW112-스테인리스 스틸 커튼월 | 0.803768 | CW112-스테인리스 스틸 커튼월 | 2 | ID 데이터 - 마크: 13; 해설: SSD; 구속조건 - 매스와 관련됨: no; 룸 경계: yes; 벽 베이스가 부착됩니다.: no; 상단이 부착됩니다.: no; 베이스 구속조건: 지상 6층; 상단 구속조건: 상위 레벨: 지상 7층; 미연결 높이: 2020 mm; 베이스 간격띄우기: 80 mm; 상단 간격띄우기: -2000 mm; 구조 - 구조: no; 구조적 용도: 비교좌장치; 단면형상 정의 - 단면형상: 수직; 수직 그리드 - 각도: 0 deg; 간격띄우기: 0 mm; 맞춤: 시작; 번호: 4; sets with these values: 2; 치수 - 길이: 1300.01 mm; BaseQuantities - Area: 0.803768 m2
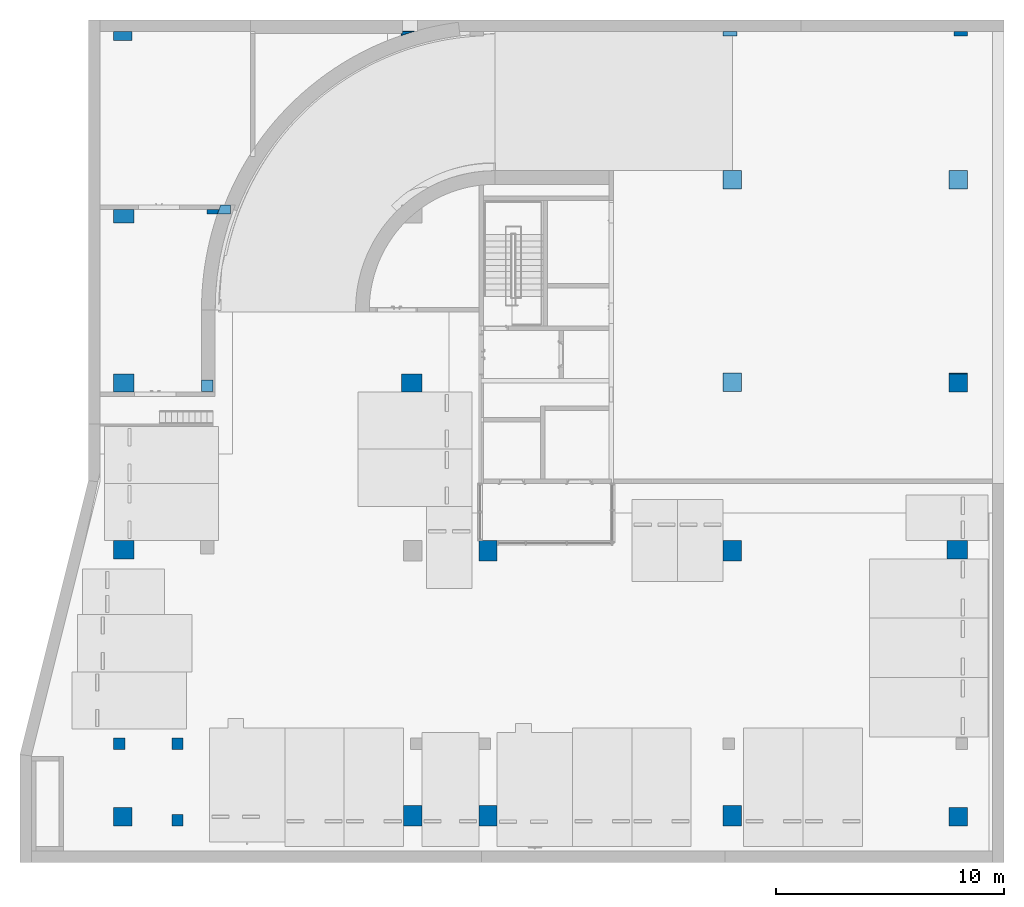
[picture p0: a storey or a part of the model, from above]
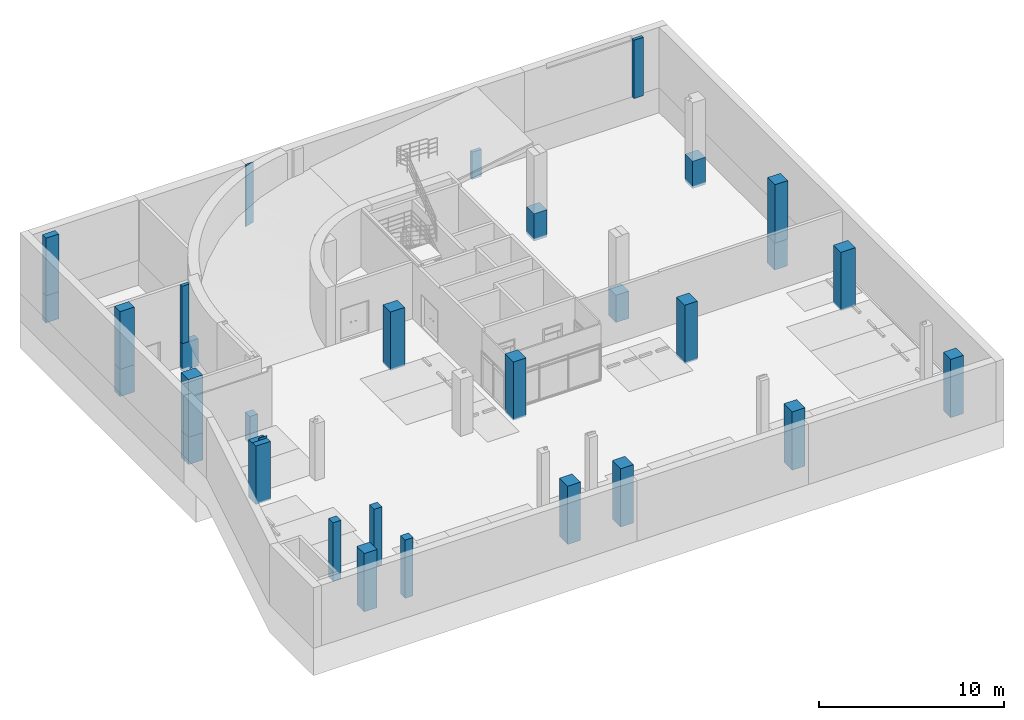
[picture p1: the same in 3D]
Properties of the parts of a building model (IFC2X3), part 24 of 39

# IfcOpeningElement: Opening (863)
Name | In | Depth (mm) | Height (mm) | Width (mm) | 생성 공정 | 카테고리 | 유형 | 유형 ID | 패밀리 | 패밀리 및 유형 | 면적 (m2) | Reference | Pset_OpeningElementCommon, sets with these values
기본 벽:WA111-철근콘크리트구조 벽 200mm_CW1:2821649 | 지상 7층 | 3048 | 1000 | 1600 | 새 구성 | 창 | WD812-미들창(스테인리스 스틸) 하부개폐 1000x1600mm | 7464744 | WD812-미들창(스테인리스 스틸) | WD812-미들창(스테인리스 스틸): WD812-미들창(스테인리스 스틸) 하부개폐 1000x1600mm | 2.46752 | WD812-미들창(스테인리스 스틸) 하부개폐 1000x1600mm | 2 | 구속조건 - 레벨: 지상 6층; 씰 높이: 3030 mm; 기타 - 창의개폐비: 50; 헤드 높이: 4630 mm; 호스트 ID: 2821453; 치수 - 벽체 opening 면적: 1.6 m2; 체적: 0.0593112 m3
기본 벽:WA111-철근콘크리트구조 벽 200mm_CW1:2821655:1 | 지상 7층 |  |  |  |  |  |  |  |  |  |  | WA111-철근콘크리트구조 벽 200mm_CW1 | 2
기본 벽:WA111-철근콘크리트구조 벽 200mm_CW1:2821687 | 지상 7층 | 504.8 |  |  | 새 구성 | 벽 | CW112-스테인리스 스틸 커튼월 | 7675291 | 커튼월 | 커튼월: CW112-스테인리스 스틸 커튼월 | 0.803768 | CW112-스테인리스 스틸 커튼월 | 2 | ID 데이터 - 마크: 13; 해설: SSD; 구속조건 - 매스와 관련됨: no; 룸 경계: yes; 벽 베이스가 부착됩니다.: no; 상단이 부착됩니다.: no; 베이스 구속조건: 지상 7층; 상단 구속조건: 상위 레벨: 지상 8층; 미연결 높이: 2020 mm; 베이스 간격띄우기: 80 mm; 상단 간격띄우기: -2000 mm; 구조 - 구조: no; 구조적 용도: 비교좌장치; 단면형상 정의 - 단면형상: 수직; 수직 그리드 - 각도: 0 deg; 간격띄우기: 0 mm; 맞춤: 시작; 번호: 4; sets with these values: 2; 치수 - 길이: 1300.01 mm; BaseQuantities - Area: 0.803768 m2
기본 벽:WA111-철근콘크리트구조 벽 200mm_CW1:2821995 | 지상 8층 | 3048 | 1000 | 1600 | 새 구성 | 창 | WD812-미들창(스테인리스 스틸) 하부개폐 1000x1600mm | 7464744 | WD812-미들창(스테인리스 스틸) | WD812-미들창(스테인리스 스틸): WD812-미들창(스테인리스 스틸) 하부개폐 1000x1600mm | 2.46752 | WD812-미들창(스테인리스 스틸) 하부개폐 1000x1600mm | 2 | 구속조건 - 레벨: 지상 7층; 씰 높이: 3030 mm; 기타 - 창의개폐비: 50; 헤드 높이: 4630 mm; 호스트 ID: 2821649; 치수 - 벽체 opening 면적: 1.6 m2; 체적: 0.0593112 m3
기본 벽:WA111-철근콘크리트구조 벽 200mm_CW1:2822033 | 지상 8층 | 504.8 |  |  | 새 구성 | 벽 | CW112-스테인리스 스틸 커튼월 | 7675291 | 커튼월 | 커튼월: CW112-스테인리스 스틸 커튼월 | 0.803768 | CW112-스테인리스 스틸 커튼월 | 2 | ID 데이터 - 마크: 13; 해설: SSD; 구속조건 - 매스와 관련됨: no; 룸 경계: yes; 벽 베이스가 부착됩니다.: no; 상단이 부착됩니다.: no; 베이스 구속조건: 지상 8층; 상단 구속조건: 상위 레벨: 지상 9층; 미연결 높이: 2020 mm; 베이스 간격띄우기: 80 mm; 상단 간격띄우기: -2000 mm; 구조 - 구조: no; 구조적 용도: 비교좌장치; 단면형상 정의 - 단면형상: 수직; 수직 그리드 - 각도: 0 deg; 간격띄우기: 0 mm; 맞춤: 시작; 번호: 4; sets with these values: 2; 치수 - 길이: 1300.01 mm; BaseQuantities - Area: 0.803768 m2
기본 벽:WA111-철근콘크리트구조 벽 200mm_CW1:2822201 | 지상 9층 | 3048 | 1000 | 1600 | 새 구성 | 창 | WD812-미들창(스테인리스 스틸) 하부개폐 1000x1600mm | 7464744 | WD812-미들창(스테인리스 스틸) | WD812-미들창(스테인리스 스틸): WD812-미들창(스테인리스 스틸) 하부개폐 1000x1600mm | 2.46752 | WD812-미들창(스테인리스 스틸) 하부개폐 1000x1600mm | 2 | 구속조건 - 레벨: 지상 8층; 씰 높이: 3030 mm; 기타 - 창의개폐비: 50; 헤드 높이: 4630 mm; 호스트 ID: 2821995; 치수 - 벽체 opening 면적: 1.6 m2; 체적: 0.0593112 m3
기본 벽:WA111-철근콘크리트구조 벽 200mm_CW1:2822239 | 지상 9층 | 504.8 |  |  | 새 구성 | 벽 | CW112-스테인리스 스틸 커튼월 | 7675291 | 커튼월 | 커튼월: CW112-스테인리스 스틸 커튼월 | 0.803768 | CW112-스테인리스 스틸 커튼월 | 2 | ID 데이터 - 마크: 13; 해설: SSD; 구속조건 - 매스와 관련됨: no; 룸 경계: yes; 벽 베이스가 부착됩니다.: no; 상단이 부착됩니다.: no; 베이스 구속조건: 지상 9층; 상단 구속조건: 상위 레벨: 지상 10층; 미연결 높이: 2020 mm; 베이스 간격띄우기: 80 mm; 상단 간격띄우기: -2400 mm; 구조 - 구조: no; 구조적 용도: 비교좌장치; 단면형상 정의 - 단면형상: 수직; 수직 그리드 - 각도: 0 deg; 간격띄우기: 0 mm; 맞춤: 시작; 번호: 4; sets with these values: 2; 치수 - 길이: 1300.01 mm; BaseQuantities - Area: 0.803768 m2
기본 벽:(복합)A2-22-02A+WA111(200_CW1)+A1-32-06A_압출+철콘+수성:2822387 | 지상 10층 | 3048 | 1000 | 1600 | 새 구성 | 창 | WD812-미들창(스테인리스 스틸) 하부개폐 1000x1600mm | 7464744 | WD812-미들창(스테인리스 스틸) | WD812-미들창(스테인리스 스틸): WD812-미들창(스테인리스 스틸) 하부개폐 1000x1600mm | 2.46752 | WD812-미들창(스테인리스 스틸) 하부개폐 1000x1600mm | 2 | 구속조건 - 레벨: 지상 9층; 씰 높이: 3415.8 mm; 기타 - 창의개폐비: 50; 헤드 높이: 5015.8 mm; 호스트 ID: 2822201; 치수 - 벽체 opening 면적: 1.6 m2; 체적: 0.0593112 m3
기본 벽:(복합)WA313+WA111(200_CW1)+A1-32-06A_화강석잔다듬+철콘+수성:2822425 | 지상 10층 | 602.8 |  |  | 새 구성 | 벽 | CW112-스테인리스 스틸 커튼월 | 7675291 | 커튼월 | 커튼월: CW112-스테인리스 스틸 커튼월 | 1.22797 | CW112-스테인리스 스틸 커튼월 | 2 | ID 데이터 - 마크: 13; 해설: SSD; 구속조건 - 매스와 관련됨: no; 룸 경계: yes; 벽 베이스가 부착됩니다.: no; 상단이 부착됩니다.: no; 베이스 구속조건: 지상 10층; 상단 구속조건: 상위 레벨: 옥탑층; 미연결 높이: 2020 mm; 베이스 간격띄우기: 80 mm; 상단 간격띄우기: -2900 mm; 구조 - 구조: no; 구조적 용도: 비교좌장치; 단면형상 정의 - 단면형상: 수직; 수직 그리드 - 각도: 0 deg; 간격띄우기: 0 mm; 맞춤: 시작; 번호: 4; sets with these values: 2; 치수 - 길이: 1510.01 mm; BaseQuantities - Area: 1.22797 m2
기본 벽:WA111-철근콘크리트구조 벽 200mm_CW1:2822811 | 옥탑층 | 3048 | 1000 | 1600 | 새 구성 | 창 | WD812-미들창(스테인리스 스틸) 하부개폐 1000x1600mm | 7464744 | WD812-미들창(스테인리스 스틸) | WD812-미들창(스테인리스 스틸): WD812-미들창(스테인리스 스틸) 하부개폐 1000x1600mm | 2.46752 | WD812-미들창(스테인리스 스틸) 하부개폐 1000x1600mm | 2 | 구속조건 - 레벨: 지상 10층; 씰 높이: 3919.8 mm; 기타 - 창의개폐비: 50; 헤드 높이: 5519.8 mm; 호스트 ID: 2822387; 치수 - 벽체 opening 면적: 1.6 m2; 체적: 0.0593112 m3
기본 벽:WA111-철근콘크리트구조 벽 200mm_CW1:2822839:1 | 옥탑층 | 3850 |  |  |  |  |  |  |  |  |  | WA111-철근콘크리트구조 벽 200mm_CW1 | 2 | BaseQuantities - Area: 1.29731 m2
기본 벽:WA313-화강석잔다듬 벽 (30, 건식50) 80mm:2830676 | 지상 1층 | 384.8 | 7200.02 | 3520 | 새 구성 | 벽 | CW112-스테인리스 스틸 커튼월 | 7675291 | 커튼월 | 커튼월: CW112-스테인리스 스틸 커튼월 | 25.3441 | CW112-스테인리스 스틸 커튼월 | 2 | ID 데이터 - 마크: 2; 해설: SSD; 구속조건 - 매스와 관련됨: no; 룸 경계: yes; 벽 베이스가 부착됩니다.: no; 상단이 부착됩니다.: no; 베이스 구속조건: 지상 1층; 상단 구속조건: 상위 레벨: 지상 2층; 미연결 높이: 3520 mm; 베이스 간격띄우기: 80 mm; 상단 간격띄우기: -1200 mm; 구조 - 구조: no; 구조적 용도: 비교좌장치; 단면형상 정의 - 단면형상: 수직; 수직 그리드 - 각도: 0 deg; 간격띄우기: 0 mm; 맞춤: 시작; 번호: 4; sets with these values: 2; 치수 - 길이: 7200.02 mm
기본 벽:WA313-화강석잔다듬 벽 (30, 건식50) 80mm:2830676 | 지상 1층 | 384.8 | 6600 | 3520 | 새 구성 | 벽 | CW112-스테인리스 스틸 커튼월 | 7675291 | 커튼월 | 커튼월: CW112-스테인리스 스틸 커튼월 | 23.232 | CW112-스테인리스 스틸 커튼월 | 2 | ID 데이터 - 마크: 3; 해설: SSD; 구속조건 - 매스와 관련됨: no; 룸 경계: yes; 벽 베이스가 부착됩니다.: no; 상단이 부착됩니다.: no; 베이스 구속조건: 지상 1층; 상단 구속조건: 상위 레벨: 지상 2층; 미연결 높이: 3520 mm; 베이스 간격띄우기: 80 mm; 상단 간격띄우기: -1200 mm; 구조 - 구조: no; 구조적 용도: 비교좌장치; 단면형상 정의 - 단면형상: 수직; 수직 그리드 - 각도: 0 deg; 간격띄우기: 0 mm; 맞춤: 시작; 번호: 4; sets with these values: 2; 치수 - 길이: 6600 mm
기본 벽:WA313-화강석잔다듬 벽 (30, 건식50) 80mm:2830676 | 지상 1층 | 384.8 | 10900 | 3520 | 새 구성 | 벽 | CW112-스테인리스 스틸 커튼월 | 7675291 | 커튼월 | 커튼월: CW112-스테인리스 스틸 커튼월 | 38.3679 | CW112-스테인리스 스틸 커튼월 | 2 | ID 데이터 - 마크: 5; 해설: SSD; 구속조건 - 매스와 관련됨: no; 룸 경계: yes; 벽 베이스가 부착됩니다.: no; 상단이 부착됩니다.: no; 베이스 구속조건: 지상 1층; 상단 구속조건: 상위 레벨: 지상 2층; 미연결 높이: 3520 mm; 베이스 간격띄우기: 80 mm; 상단 간격띄우기: -1200 mm; 구조 - 구조: no; 구조적 용도: 비교좌장치; 단면형상 정의 - 단면형상: 수직; 수직 그리드 - 각도: 0 deg; 간격띄우기: 0 mm; 맞춤: 시작; 번호: 4; sets with these values: 2; 치수 - 길이: 10900 mm
기본 벽:WA313-화강석잔다듬 벽 (30, 건식50) 80mm:2831445 | 지상 1층 | 384.8 | 2020 | 1399.99 | 새 구성 | 벽 | CW112-스테인리스 스틸 커튼월 | 7675291 | 커튼월 | 커튼월: CW112-스테인리스 스틸 커튼월 | 2.82798 | CW112-스테인리스 스틸 커튼월 | 2 | ID 데이터 - 마크: 13; 해설: SSD; 구속조건 - 매스와 관련됨: no; 룸 경계: yes; 벽 베이스가 부착됩니다.: no; 상단이 부착됩니다.: no; 베이스 구속조건: 지상 1층; 상단 구속조건: 상위 레벨: 지상 2층; 미연결 높이: 2020 mm; 베이스 간격띄우기: -470 mm; 상단 간격띄우기: -3250 mm; 구조 - 구조: no; 구조적 용도: 비교좌장치; 단면형상 정의 - 단면형상: 수직; 수직 그리드 - 각도: 0 deg; 간격띄우기: 0 mm; 맞춤: 시작; 번호: 4; sets with these values: 2; 치수 - 길이: 1700 mm
기본 벽:A2-22-02A-압출스티로폼, BRACKET(STEEL), ALC블록 (150mm):2831632 | 지상 1층 | 3048 | 1600 | 1000 | 새 구성 | 창 | WD812-미들창(스테인리스 스틸) 하부개폐 1000x1600mm | 7464744 | WD812-미들창(스테인리스 스틸) | WD812-미들창(스테인리스 스틸): WD812-미들창(스테인리스 스틸) 하부개폐 1000x1600mm | 2.46752 | WD812-미들창(스테인리스 스틸) 하부개폐 1000x1600mm | 2 | 구속조건 - 레벨: 지상 1층; 씰 높이: 3600 mm; 기타 - 창의개폐비: 50; 헤드 높이: 5200 mm; 호스트 ID: 2818037; 치수 - 벽체 opening 면적: 1.6 m2; 체적: 0.0593112 m3
기본 벽:A2-22-02A-압출스티로폼, BRACKET(STEEL), ALC블록 (150mm):2831632 | 지상 1층 | 3048 | 800 | 1200 | 새 구성 | 창 | WD812-미들창(스테인리스 스틸) 하부개폐 800x1200mm | 7464739 | WD812-미들창(스테인리스 스틸) | WD812-미들창(스테인리스 스틸): WD812-미들창(스테인리스 스틸) 하부개폐 800x1200mm | 1.62992 | WD812-미들창(스테인리스 스틸) 하부개폐 800x1200mm | 2 | 구속조건 - 레벨: 지상 1층; 씰 높이: 400 mm; 기타 - 창의개폐비: 50; 헤드 높이: 1600 mm; 호스트 ID: 2818037; 치수 - 벽체 opening 면적: 0.96 m2; 체적: 0.0421992 m3
기본 벽:A2-22-02A-압출스티로폼, BRACKET(STEEL), ALC블록 (150mm):2831799 | 지상 1층 | 454.8 | 3520 | 1200 | 새 구성 | 벽 | CW112-스테인리스 스틸 커튼월 | 7675291 | 커튼월 | 커튼월: CW112-스테인리스 스틸 커튼월 | 4.224 | CW112-스테인리스 스틸 커튼월 | 2 | ID 데이터 - 마크: 14; 해설: SSD; 구속조건 - 매스와 관련됨: no; 룸 경계: yes; 벽 베이스가 부착됩니다.: no; 상단이 부착됩니다.: no; 베이스 구속조건: 지상 1층; 상단 구속조건: 상위 레벨: 지상 2층; 미연결 높이: 3520 mm; 베이스 간격띄우기: 80 mm; 상단 간격띄우기: -1200 mm; 구조 - 구조: no; 구조적 용도: 비교좌장치; 단면형상 정의 - 단면형상: 수직; 수직 그리드 - 각도: 0 deg; 간격띄우기: 0 mm; 맞춤: 시작; 번호: 4; sets with these values: 2; 치수 - 길이: 1200 mm
기본 벽:A2-22-02A-압출스티로폼, BRACKET(STEEL), ALC블록 (150mm):2831799 | 지상 1층 | 3048 | 2000 | 1800 | 새 구성 | 창 | WD842-2단 하부 더블 프로젝트 창(스테인리스 스틸)_2000x1800mm | 7468501 | WD842-2단 하부 더블 프로젝트 창(스테인리스 스틸) | WD842-2단 하부 더블 프로젝트 창(스테인리스 스틸): WD842-2단 하부 더블 프로젝트 창(스테인리스 스틸)_2000x1800mm | 5.10973 | WD842-2단 하부 더블 프로젝트 창(스테인리스 스틸)_2000x1800mm | 2 | 구속조건 - 레벨: 지상 1층; 씰 높이: 1000 mm; 기타 - 창의개폐비: 100; 헤드 높이: 2800 mm; 호스트 ID: 2818398; 치수 - 체적: 0.113019 m3
기본 벽:WA731-DRY WALL(C50, GS12.5mm) (1겹한면, GW50mm) 62.5mm:2831868 | 지상 1층 | 367.3 | 2593.15 | 3520 | 새 구성 | 벽 | CW112-스테인리스 스틸 커튼월 | 7675291 | 커튼월 | 커튼월: CW112-스테인리스 스틸 커튼월 | 9.1279 | CW112-스테인리스 스틸 커튼월 | 2 | ID 데이터 - 마크: 24; 해설: SSD; 구속조건 - 매스와 관련됨: no; 룸 경계: yes; 벽 베이스가 부착됩니다.: no; 상단이 부착됩니다.: no; 베이스 구속조건: 지상 1층; 상단 구속조건: 상위 레벨: 지상 2층; 미연결 높이: 3520 mm; 베이스 간격띄우기: 80 mm; 상단 간격띄우기: -1200 mm; 구조 - 구조: no; 구조적 용도: 비교좌장치; 단면형상 정의 - 단면형상: 수직; 수직 그리드 - 각도: 0 deg; 간격띄우기: 0 mm; 맞춤: 시작; 번호: 4; sets with these values: 2; 치수 - 길이: 2693.15 mm
기본 벽:WA313-화강석잔다듬 벽 (30, 건식50) 80mm:2834832 | 지상 2층 | 384.8 | 7210 | 3120 | 새 구성 | 벽 | CW112-스테인리스 스틸 커튼월 | 7675291 | 커튼월 | 커튼월: CW112-스테인리스 스틸 커튼월 | 22.4952 | CW112-스테인리스 스틸 커튼월 | 2 | ID 데이터 - 마크: 5; 해설: AW; 구속조건 - 매스와 관련됨: no; 룸 경계: yes; 벽 베이스가 부착됩니다.: no; 상단이 부착됩니다.: no; 베이스 구속조건: 지상 2층; 상단 구속조건: 상위 레벨: 지상 3층; 미연결 높이: 3120 mm; 베이스 간격띄우기: 80 mm; 상단 간격띄우기: -1300 mm; 구조 - 구조: no; 구조적 용도: 비교좌장치; 단면형상 정의 - 단면형상: 수직; 수직 그리드 - 각도: 0 deg; 간격띄우기: 0 mm; 맞춤: 시작; 번호: 4; sets with these values: 2; 치수 - 길이: 7210 mm
기본 벽:WA313-화강석잔다듬 벽 (30, 건식50) 80mm:2834832 | 지상 2층 | 384.8 | 6600 | 3120 | 새 구성 | 벽 | CW112-스테인리스 스틸 커튼월 | 7675291 | 커튼월 | 커튼월: CW112-스테인리스 스틸 커튼월 | 20.592 | CW112-스테인리스 스틸 커튼월 | 2 | ID 데이터 - 마크: 6; 해설: AW; 구속조건 - 매스와 관련됨: no; 룸 경계: yes; 벽 베이스가 부착됩니다.: no; 상단이 부착됩니다.: no; 베이스 구속조건: 지상 2층; 상단 구속조건: 상위 레벨: 지상 3층; 미연결 높이: 3120 mm; 베이스 간격띄우기: 80 mm; 상단 간격띄우기: -1300 mm; 구조 - 구조: no; 구조적 용도: 비교좌장치; 단면형상 정의 - 단면형상: 수직; 수직 그리드 - 각도: 0 deg; 간격띄우기: 0 mm; 맞춤: 시작; 번호: 4; sets with these values: 2; 치수 - 길이: 6600 mm
기본 벽:WA313-화강석잔다듬 벽 (30, 건식50) 80mm:2834832 | 지상 2층 | 384.8 | 6500 | 3120 | 새 구성 | 벽 | CW112-스테인리스 스틸 커튼월 | 7675291 | 커튼월 | 커튼월: CW112-스테인리스 스틸 커튼월 | 20.28 | CW112-스테인리스 스틸 커튼월 | 2 | ID 데이터 - 마크: 7; 해설: AW; 구속조건 - 매스와 관련됨: no; 룸 경계: yes; 벽 베이스가 부착됩니다.: no; 상단이 부착됩니다.: no; 베이스 구속조건: 지상 2층; 상단 구속조건: 상위 레벨: 지상 3층; 미연결 높이: 3120 mm; 베이스 간격띄우기: 80 mm; 상단 간격띄우기: -1300 mm; 구조 - 구조: no; 구조적 용도: 비교좌장치; 단면형상 정의 - 단면형상: 수직; 수직 그리드 - 각도: 0 deg; 간격띄우기: 0 mm; 맞춤: 시작; 번호: 4; sets with these values: 2; 치수 - 길이: 6500 mm
기본 벽:WA313-화강석잔다듬 벽 (30, 건식50) 80mm:2834832 | 지상 2층 | 384.8 | 5357 | 3120 | 새 구성 | 벽 | CW112-스테인리스 스틸 커튼월 | 7675291 | 커튼월 | 커튼월: CW112-스테인리스 스틸 커튼월 | 16.7138 | CW112-스테인리스 스틸 커튼월 | 2 | ID 데이터 - 마크: 8; 해설: AW; 구속조건 - 매스와 관련됨: no; 룸 경계: yes; 벽 베이스가 부착됩니다.: no; 상단이 부착됩니다.: no; 베이스 구속조건: 지상 2층; 상단 구속조건: 상위 레벨: 지상 3층; 미연결 높이: 3120 mm; 베이스 간격띄우기: 80 mm; 상단 간격띄우기: -1300 mm; 구조 - 구조: no; 구조적 용도: 비교좌장치; 단면형상 정의 - 단면형상: 수직; 수직 그리드 - 각도: 0 deg; 간격띄우기: 0 mm; 맞춤: 시작; 번호: 4; sets with these values: 2; 치수 - 길이: 5366 mm
기본 벽:WA313-화강석잔다듬 벽 (30, 건식50) 80mm:2834832 | 지상 2층 | 384.8 | 4322.75 | 3120 | 새 구성 | 벽 | CW112-스테인리스 스틸 커튼월 | 7675291 | 커튼월 | 커튼월: CW112-스테인리스 스틸 커튼월 | 13.487 | CW112-스테인리스 스틸 커튼월 | 2 | ID 데이터 - 마크: 9; 해설: AW; 구속조건 - 매스와 관련됨: no; 룸 경계: yes; 벽 베이스가 부착됩니다.: no; 상단이 부착됩니다.: no; 베이스 구속조건: 지상 2층; 상단 구속조건: 상위 레벨: 지상 3층; 미연결 높이: 3120 mm; 베이스 간격띄우기: 80 mm; 상단 간격띄우기: -1300 mm; 구조 - 구조: no; 구조적 용도: 비교좌장치; 단면형상 정의 - 단면형상: 수직; 수직 그리드 - 각도: 0 deg; 간격띄우기: 0 mm; 맞춤: 시작; 번호: 4; sets with these values: 2; 치수 - 길이: 4322.75 mm
기본 벽:WA313-화강석잔다듬 벽 (30, 건식50) 80mm:2834833 | 지상 2층 | 384.8 | 5432.03 | 3120 | 새 구성 | 벽 | CW112-스테인리스 스틸 커튼월 | 7675291 | 커튼월 | 커튼월: CW112-스테인리스 스틸 커튼월 | 16.9479 | CW112-스테인리스 스틸 커튼월 | 2 | ID 데이터 - 마크: 10; 해설: AW; 구속조건 - 매스와 관련됨: no; 룸 경계: yes; 벽 베이스가 부착됩니다.: no; 상단이 부착됩니다.: no; 베이스 구속조건: 지상 2층; 상단 구속조건: 상위 레벨: 지상 3층; 미연결 높이: 3120 mm; 베이스 간격띄우기: 80 mm; 상단 간격띄우기: -1300 mm; 구조 - 구조: no; 구조적 용도: 비교좌장치; 단면형상 정의 - 단면형상: 수직; 수직 그리드 - 각도: 0 deg; 간격띄우기: 0 mm; 맞춤: 시작; 번호: 4; sets with these values: 2; 치수 - 길이: 5441.03 mm
기본 벽:WA313-화강석잔다듬 벽 (30, 건식50) 80mm:2834833 | 지상 2층 | 384.8 | 5450.11 | 3120 | 새 구성 | 벽 | CW112-스테인리스 스틸 커튼월 | 7675291 | 커튼월 | 커튼월: CW112-스테인리스 스틸 커튼월 | 17.0044 | CW112-스테인리스 스틸 커튼월 | 2 | ID 데이터 - 마크: 11; 해설: AW; 구속조건 - 매스와 관련됨: no; 룸 경계: yes; 벽 베이스가 부착됩니다.: no; 상단이 부착됩니다.: no; 베이스 구속조건: 지상 2층; 상단 구속조건: 상위 레벨: 지상 3층; 미연결 높이: 3120 mm; 베이스 간격띄우기: 80 mm; 상단 간격띄우기: -1300 mm; 구조 - 구조: no; 구조적 용도: 비교좌장치; 단면형상 정의 - 단면형상: 수직; 수직 그리드 - 각도: 0 deg; 간격띄우기: 0 mm; 맞춤: 시작; 번호: 4; sets with these values: 2; 치수 - 길이: 5450.11 mm
기본 벽:WA313-화강석잔다듬 벽 (30, 건식50) 80mm:2834833 | 지상 2층 | 384.8 | 2500 | 3120 | 새 구성 | 벽 | CW112-스테인리스 스틸 커튼월 | 7675291 | 커튼월 | 커튼월: CW112-스테인리스 스틸 커튼월 | 7.8 | CW112-스테인리스 스틸 커튼월 | 2 | ID 데이터 - 마크: 12; 해설: AW; 구속조건 - 매스와 관련됨: no; 룸 경계: yes; 벽 베이스가 부착됩니다.: no; 상단이 부착됩니다.: no; 베이스 구속조건: 지상 2층; 상단 구속조건: 상위 레벨: 지상 3층; 미연결 높이: 3120 mm; 베이스 간격띄우기: 80 mm; 상단 간격띄우기: -1300 mm; 구조 - 구조: no; 구조적 용도: 비교좌장치; 단면형상 정의 - 단면형상: 수직; 수직 그리드 - 각도: 0 deg; 간격띄우기: 0 mm; 맞춤: 시작; 번호: 4; sets with these values: 2; 치수 - 길이: 2500 mm
기본 벽:WA313-화강석잔다듬 벽 (30, 건식50) 80mm:2834833 | 지상 2층 | 384.8 | 4457.27 | 3120 | 새 구성 | 벽 | CW112-스테인리스 스틸 커튼월 | 7675291 | 커튼월 | 커튼월: CW112-스테인리스 스틸 커튼월 | 13.9067 | CW112-스테인리스 스틸 커튼월 | 2 | ID 데이터 - 마크: 13; 해설: AW; 구속조건 - 매스와 관련됨: no; 룸 경계: yes; 벽 베이스가 부착됩니다.: no; 상단이 부착됩니다.: no; 베이스 구속조건: 지상 2층; 상단 구속조건: 상위 레벨: 지상 3층; 미연결 높이: 3120 mm; 베이스 간격띄우기: 80 mm; 상단 간격띄우기: -1300 mm; 구조 - 구조: no; 구조적 용도: 비교좌장치; 단면형상 정의 - 단면형상: 수직; 수직 그리드 - 각도: 0 deg; 간격띄우기: 0 mm; 맞춤: 시작; 번호: 4; sets with these values: 2; 치수 - 길이: 4466.27 mm
기본 벽:WA313-화강석잔다듬 벽 (30, 건식50) 80mm:2834833 | 지상 2층 | 384.8 | 4449.82 | 3120 | 새 구성 | 벽 | CW112-스테인리스 스틸 커튼월 | 7675291 | 커튼월 | 커튼월: CW112-스테인리스 스틸 커튼월 | 13.8835 | CW112-스테인리스 스틸 커튼월 | 2 | ID 데이터 - 마크: 14; 해설: AW; 구속조건 - 매스와 관련됨: no; 룸 경계: yes; 벽 베이스가 부착됩니다.: no; 상단이 부착됩니다.: no; 베이스 구속조건: 지상 2층; 상단 구속조건: 상위 레벨: 지상 3층; 미연결 높이: 3120 mm; 베이스 간격띄우기: 80 mm; 상단 간격띄우기: -1300 mm; 구조 - 구조: no; 구조적 용도: 비교좌장치; 단면형상 정의 - 단면형상: 수직; 수직 그리드 - 각도: 0 deg; 간격띄우기: 0 mm; 맞춤: 시작; 번호: 4; sets with these values: 2; 치수 - 길이: 4449.82 mm
기본 벽:WA313-화강석잔다듬 벽 (30, 건식50) 80mm:2834833 | 지상 2층 | 384.8 | 4026.1 | 3120 | 새 구성 | 벽 | CW112-스테인리스 스틸 커튼월 | 7675291 | 커튼월 | 커튼월: CW112-스테인리스 스틸 커튼월 | 12.5614 | CW112-스테인리스 스틸 커튼월 | 2 | ID 데이터 - 마크: 15; 해설: AW; 구속조건 - 매스와 관련됨: no; 룸 경계: yes; 벽 베이스가 부착됩니다.: no; 상단이 부착됩니다.: no; 베이스 구속조건: 지상 2층; 상단 구속조건: 상위 레벨: 지상 3층; 미연결 높이: 3120 mm; 베이스 간격띄우기: 80 mm; 상단 간격띄우기: -1300 mm; 구조 - 구조: no; 구조적 용도: 비교좌장치; 단면형상 정의 - 단면형상: 수직; 수직 그리드 - 각도: 0 deg; 간격띄우기: 0 mm; 맞춤: 시작; 번호: 4; sets with these values: 2; 치수 - 길이: 4026.1 mm
기본 벽:WA313-화강석잔다듬 벽 (30, 건식50) 80mm:2834833 | 지상 2층 | 384.8 | 4039.16 | 3120 | 새 구성 | 벽 | CW112-스테인리스 스틸 커튼월 | 7675291 | 커튼월 | 커튼월: CW112-스테인리스 스틸 커튼월 | 12.6022 | CW112-스테인리스 스틸 커튼월 | 2 | ID 데이터 - 마크: 16; 해설: AW; 구속조건 - 매스와 관련됨: no; 룸 경계: yes; 벽 베이스가 부착됩니다.: no; 상단이 부착됩니다.: no; 베이스 구속조건: 지상 2층; 상단 구속조건: 상위 레벨: 지상 3층; 미연결 높이: 3120 mm; 베이스 간격띄우기: 80 mm; 상단 간격띄우기: -1300 mm; 구조 - 구조: no; 구조적 용도: 비교좌장치; 단면형상 정의 - 단면형상: 수직; 수직 그리드 - 각도: 0 deg; 간격띄우기: 0 mm; 맞춤: 시작; 번호: 4; sets with these values: 2; 치수 - 길이: 4048.16 mm
기본 벽:WA313-화강석잔다듬 벽 (30, 건식50) 80mm:2834834 | 지상 2층 | 384.8 | 4907 | 3120 | 새 구성 | 벽 | CW112-스테인리스 스틸 커튼월 | 7675291 | 커튼월 | 커튼월: CW112-스테인리스 스틸 커튼월 | 15.3098 | CW112-스테인리스 스틸 커튼월 | 2 | ID 데이터 - 마크: 17; 해설: AW; 구속조건 - 매스와 관련됨: no; 룸 경계: yes; 벽 베이스가 부착됩니다.: no; 상단이 부착됩니다.: no; 베이스 구속조건: 지상 2층; 상단 구속조건: 상위 레벨: 지상 3층; 미연결 높이: 3120 mm; 베이스 간격띄우기: 80 mm; 상단 간격띄우기: -1300 mm; 구조 - 구조: no; 구조적 용도: 비교좌장치; 단면형상 정의 - 단면형상: 수직; 수직 그리드 - 각도: 0 deg; 간격띄우기: 0 mm; 맞춤: 시작; 번호: 4; sets with these values: 2; 치수 - 길이: 4916 mm
기본 벽:WA313-화강석잔다듬 벽 (30, 건식50) 80mm:2834834 | 지상 2층 | 384.8 | 4907 | 3120 | 새 구성 | 벽 | CW112-스테인리스 스틸 커튼월 | 7675291 | 커튼월 | 커튼월: CW112-스테인리스 스틸 커튼월 | 15.3098 | CW112-스테인리스 스틸 커튼월 | 2 | ID 데이터 - 마크: 18; 해설: AW; 구속조건 - 매스와 관련됨: no; 룸 경계: yes; 벽 베이스가 부착됩니다.: no; 상단이 부착됩니다.: no; 베이스 구속조건: 지상 2층; 상단 구속조건: 상위 레벨: 지상 3층; 미연결 높이: 3120 mm; 베이스 간격띄우기: 80 mm; 상단 간격띄우기: -1300 mm; 구조 - 구조: no; 구조적 용도: 비교좌장치; 단면형상 정의 - 단면형상: 수직; 수직 그리드 - 각도: 0 deg; 간격띄우기: 0 mm; 맞춤: 시작; 번호: 4; sets with these values: 2; 치수 - 길이: 4916 mm
기본 벽:WA313-화강석잔다듬 벽 (30, 건식50) 80mm:2834834 | 지상 2층 | 384.8 | 6482 | 3120 | 새 구성 | 벽 | CW112-스테인리스 스틸 커튼월 | 7675291 | 커튼월 | 커튼월: CW112-스테인리스 스틸 커튼월 | 20.2238 | CW112-스테인리스 스틸 커튼월 | 2 | ID 데이터 - 마크: 19; 해설: AW; 구속조건 - 매스와 관련됨: no; 룸 경계: yes; 벽 베이스가 부착됩니다.: no; 상단이 부착됩니다.: no; 베이스 구속조건: 지상 2층; 상단 구속조건: 상위 레벨: 지상 3층; 미연결 높이: 3120 mm; 베이스 간격띄우기: 80 mm; 상단 간격띄우기: -1300 mm; 구조 - 구조: no; 구조적 용도: 비교좌장치; 단면형상 정의 - 단면형상: 수직; 수직 그리드 - 각도: 0 deg; 간격띄우기: 0 mm; 맞춤: 시작; 번호: 4; sets with these values: 2; 치수 - 길이: 6491 mm
기본 벽:WA313-화강석잔다듬 벽 (30, 건식50) 80mm:2834834 | 지상 2층 | 384.8 | 8100 | 3120 | 새 구성 | 벽 | CW112-스테인리스 스틸 커튼월 | 7675291 | 커튼월 | 커튼월: CW112-스테인리스 스틸 커튼월 | 25.272 | CW112-스테인리스 스틸 커튼월 | 2 | ID 데이터 - 마크: 20; 해설: AW; 구속조건 - 매스와 관련됨: no; 룸 경계: yes; 벽 베이스가 부착됩니다.: no; 상단이 부착됩니다.: no; 베이스 구속조건: 지상 2층; 상단 구속조건: 상위 레벨: 지상 3층; 미연결 높이: 3120 mm; 베이스 간격띄우기: 80 mm; 상단 간격띄우기: -1300 mm; 구조 - 구조: no; 구조적 용도: 비교좌장치; 단면형상 정의 - 단면형상: 수직; 수직 그리드 - 각도: 0 deg; 간격띄우기: 0 mm; 맞춤: 시작; 번호: 4; sets with these values: 2; 치수 - 길이: 8100 mm
기본 벽:WA313-화강석잔다듬 벽 (30, 건식50) 80mm:2834835 | 지상 2층 | 384.8 | 8970.43 | 3120 | 새 구성 | 벽 | CW112-스테인리스 스틸 커튼월 | 7675291 | 커튼월 | 커튼월: CW112-스테인리스 스틸 커튼월 | 27.9878 | CW112-스테인리스 스틸 커튼월 | 2 | ID 데이터 - 마크: 21; 해설: AW; 구속조건 - 매스와 관련됨: no; 룸 경계: yes; 벽 베이스가 부착됩니다.: no; 상단이 부착됩니다.: no; 베이스 구속조건: 지상 2층; 상단 구속조건: 상위 레벨: 지상 3층; 미연결 높이: 3120 mm; 베이스 간격띄우기: 80 mm; 상단 간격띄우기: -1300 mm; 구조 - 구조: no; 구조적 용도: 비교좌장치; 단면형상 정의 - 단면형상: 수직; 수직 그리드 - 각도: 0 deg; 간격띄우기: 0 mm; 맞춤: 시작; 번호: 4; sets with these values: 2; 치수 - 길이: 8970.43 mm
기본 벽:A2-22-02A-압출스티로폼, BRACKET(STEEL), ALC블록 (150mm):2834839 | 지상 2층 | 3048 | 1600 | 1000 | 새 구성 | 창 | WD812-미들창(스테인리스 스틸) 하부개폐 1000x1600mm | 7464744 | WD812-미들창(스테인리스 스틸) | WD812-미들창(스테인리스 스틸): WD812-미들창(스테인리스 스틸) 하부개폐 1000x1600mm | 2.46752 | WD812-미들창(스테인리스 스틸) 하부개폐 1000x1600mm | 2 | 구속조건 - 레벨: 지상 1층; 씰 높이: 3600 mm; 기타 - 창의개폐비: 50; 헤드 높이: 5200 mm; 호스트 ID: 2818037; 치수 - 벽체 opening 면적: 1.6 m2; 체적: 0.0593112 m3
기본 벽:A2-22-02A-압출스티로폼, BRACKET(STEEL), ALC블록 (150mm):2834839 | 지상 2층 | 3048 | 1600 | 1000 | 새 구성 | 창 | WD812-미들창(스테인리스 스틸) 하부개폐 1000x1600mm | 7464744 | WD812-미들창(스테인리스 스틸) | WD812-미들창(스테인리스 스틸): WD812-미들창(스테인리스 스틸) 하부개폐 1000x1600mm | 2.46752 | WD812-미들창(스테인리스 스틸) 하부개폐 1000x1600mm | 2 | 구속조건 - 레벨: 지상 2층; 씰 높이: 3030 mm; 기타 - 창의개폐비: 50; 헤드 높이: 4630 mm; 호스트 ID: 2820022; 치수 - 벽체 opening 면적: 1.6 m2; 체적: 0.0593112 m3
기본 벽:A2-22-02A-압출스티로폼, BRACKET(STEEL), ALC블록 (150mm):2834839 | 지상 2층 | 3048 | 800 | 1200 | 새 구성 | 창 | WD812-미들창(스테인리스 스틸) 하부개폐 800x1200mm | 7464739 | WD812-미들창(스테인리스 스틸) | WD812-미들창(스테인리스 스틸): WD812-미들창(스테인리스 스틸) 하부개폐 800x1200mm | 1.62992 | WD812-미들창(스테인리스 스틸) 하부개폐 800x1200mm | 2 | 구속조건 - 레벨: 지상 2층; 씰 높이: 1200 mm; 기타 - 창의개폐비: 50; 헤드 높이: 2400 mm; 호스트 ID: 2820022; 치수 - 벽체 opening 면적: 0.96 m2; 체적: 0.0421992 m3
기본 벽:A2-22-02A-압출스티로폼, BRACKET(STEEL), ALC블록 (150mm):2834840 | 지상 2층 | 3048 | 1600 | 1500 | 새 구성 | 창 | WD842-2단 하부 더블 프로젝트 창(스테인리스 스틸)_1500x1600mm | 7468499 | WD842-2단 하부 더블 프로젝트 창(스테인리스 스틸) | WD842-2단 하부 더블 프로젝트 창(스테인리스 스틸): WD842-2단 하부 더블 프로젝트 창(스테인리스 스틸)_1500x1600mm | 3.60783 | WD842-2단 하부 더블 프로젝트 창(스테인리스 스틸)_1500x1600mm | 2 | 구속조건 - 레벨: 지상 2층; 씰 높이: 1000 mm; 기타 - 창의개폐비: 100; 헤드 높이: 2600 mm; 호스트 ID: 5998771; 치수 - 체적: 0.084837 m3
기본 벽:A2-22-02A-압출스티로폼, BRACKET(STEEL), ALC블록 (150mm):2834841 | 지상 2층 | 454.8 | 3120 | 1200 | 새 구성 | 벽 | CW112-스테인리스 스틸 커튼월 | 7675291 | 커튼월 | 커튼월: CW112-스테인리스 스틸 커튼월 | 3.744 | CW112-스테인리스 스틸 커튼월 | 2 | ID 데이터 - 마크: 0; 해설: AW; 구속조건 - 매스와 관련됨: no; 룸 경계: yes; 벽 베이스가 부착됩니다.: no; 상단이 부착됩니다.: no; 베이스 구속조건: 지상 2층; 상단 구속조건: 상위 레벨: 지상 3층; 미연결 높이: 3120 mm; 베이스 간격띄우기: 80 mm; 상단 간격띄우기: -1300 mm; 구조 - 구조: no; 구조적 용도: 비교좌장치; 단면형상 정의 - 단면형상: 수직; 수직 그리드 - 각도: 0 deg; 간격띄우기: 0 mm; 맞춤: 시작; 번호: 4; sets with these values: 2; 치수 - 길이: 1200 mm
기본 벽:A2-22-02A-압출스티로폼, BRACKET(STEEL), ALC블록 (150mm):2834841 | 지상 2층 | 3048 | 2000 | 1800 | 새 구성 | 창 | WD842-2단 하부 더블 프로젝트 창(스테인리스 스틸)_2000x1800mm | 7468501 | WD842-2단 하부 더블 프로젝트 창(스테인리스 스틸) | WD842-2단 하부 더블 프로젝트 창(스테인리스 스틸): WD842-2단 하부 더블 프로젝트 창(스테인리스 스틸)_2000x1800mm | 5.10973 | WD842-2단 하부 더블 프로젝트 창(스테인리스 스틸)_2000x1800mm | 2 | 구속조건 - 레벨: 지상 2층; 씰 높이: 1000 mm; 기타 - 창의개폐비: 100; 헤드 높이: 2800 mm; 호스트 ID: 2820046; 치수 - 체적: 0.113019 m3
기본 벽:A2-22-02A-압출스티로폼, BRACKET(STEEL), ALC블록 (150mm):2835461 | 지상 3층 | 3048 | 1600 | 1000 | 새 구성 | 창 | WD812-미들창(스테인리스 스틸) 하부개폐 1000x1600mm | 7464744 | WD812-미들창(스테인리스 스틸) | WD812-미들창(스테인리스 스틸): WD812-미들창(스테인리스 스틸) 하부개폐 1000x1600mm | 2.46752 | WD812-미들창(스테인리스 스틸) 하부개폐 1000x1600mm | 2 | 구속조건 - 레벨: 지상 3층; 씰 높이: 3030 mm; 기타 - 창의개폐비: 50; 헤드 높이: 4630 mm; 호스트 ID: 2820441; 치수 - 벽체 opening 면적: 1.6 m2; 체적: 0.0593112 m3
기본 벽:A2-22-02A-압출스티로폼, BRACKET(STEEL), ALC블록 (150mm):2835461 | 지상 3층 | 3048 | 1600 | 1000 | 새 구성 | 창 | WD812-미들창(스테인리스 스틸) 하부개폐 1000x1600mm | 7464744 | WD812-미들창(스테인리스 스틸) | WD812-미들창(스테인리스 스틸): WD812-미들창(스테인리스 스틸) 하부개폐 1000x1600mm | 2.46752 | WD812-미들창(스테인리스 스틸) 하부개폐 1000x1600mm | 2 | 구속조건 - 레벨: 지상 2층; 씰 높이: 3030 mm; 기타 - 창의개폐비: 50; 헤드 높이: 4630 mm; 호스트 ID: 2820022; 치수 - 벽체 opening 면적: 1.6 m2; 체적: 0.0593112 m3
기본 벽:A2-22-02A-압출스티로폼, BRACKET(STEEL), ALC블록 (150mm):2835461 | 지상 3층 | 3048 | 800 | 1200 | 새 구성 | 창 | WD812-미들창(스테인리스 스틸) 하부개폐 800x1200mm | 7464739 | WD812-미들창(스테인리스 스틸) | WD812-미들창(스테인리스 스틸): WD812-미들창(스테인리스 스틸) 하부개폐 800x1200mm | 1.62992 | WD812-미들창(스테인리스 스틸) 하부개폐 800x1200mm | 2 | 구속조건 - 레벨: 지상 3층; 씰 높이: 1200 mm; 기타 - 창의개폐비: 50; 헤드 높이: 2400 mm; 호스트 ID: 2820441; 치수 - 벽체 opening 면적: 0.96 m2; 체적: 0.0421992 m3
기본 벽:A2-22-02A-압출스티로폼, BRACKET(STEEL), ALC블록 (150mm):2835462 | 지상 3층 | 3048 | 1600 | 1500 | 새 구성 | 창 | WD842-2단 하부 더블 프로젝트 창(스테인리스 스틸)_1500x1600mm | 7468499 | WD842-2단 하부 더블 프로젝트 창(스테인리스 스틸) | WD842-2단 하부 더블 프로젝트 창(스테인리스 스틸): WD842-2단 하부 더블 프로젝트 창(스테인리스 스틸)_1500x1600mm | 3.60783 | WD842-2단 하부 더블 프로젝트 창(스테인리스 스틸)_1500x1600mm | 2 | 구속조건 - 레벨: 지상 3층; 씰 높이: 1000 mm; 기타 - 창의개폐비: 100; 헤드 높이: 2600 mm; 호스트 ID: 5998918; 치수 - 체적: 0.084837 m3
기본 벽:A2-22-02A-압출스티로폼, BRACKET(STEEL), ALC블록 (150mm):2835466 | 지상 4층 | 454.8 | 21810.4 | 2100 | 새 구성 | 벽 | CW112-스테인리스 스틸 커튼월 | 7675291 | 커튼월 | 커튼월: CW112-스테인리스 스틸 커튼월 | 45.8018 | CW112-스테인리스 스틸 커튼월 | 2 | ID 데이터 - 마크: 23; 해설: AW; 구속조건 - 매스와 관련됨: no; 룸 경계: yes; 벽 베이스가 부착됩니다.: no; 상단이 부착됩니다.: no; 베이스 구속조건: 지상 4층; 상단 구속조건: 상위 레벨: 지상 5층; 미연결 높이: 2100 mm; 베이스 간격띄우기: 600 mm; 상단 간격띄우기: -1400 mm; 구조 - 구조: no; 구조적 용도: 비교좌장치; 단면형상 정의 - 단면형상: 수직; 수직 그리드 - 각도: 0 deg; 간격띄우기: 0 mm; 맞춤: 시작; 번호: 4; sets with these values: 2; 치수 - 길이: 21810.4 mm
기본 벽:A2-22-02A-압출스티로폼, BRACKET(STEEL), ALC블록 (150mm):2835473 | 지상 4층 | 3048 | 1600 | 1000 | 새 구성 | 창 | WD812-미들창(스테인리스 스틸) 하부개폐 1000x1600mm | 7464744 | WD812-미들창(스테인리스 스틸) | WD812-미들창(스테인리스 스틸): WD812-미들창(스테인리스 스틸) 하부개폐 1000x1600mm | 2.46752 | WD812-미들창(스테인리스 스틸) 하부개폐 1000x1600mm | 2 | 구속조건 - 레벨: 지상 3층; 씰 높이: 3030 mm; 기타 - 창의개폐비: 50; 헤드 높이: 4630 mm; 호스트 ID: 2820441; 치수 - 벽체 opening 면적: 1.6 m2; 체적: 0.0593112 m3
기본 벽:A2-22-02A-압출스티로폼, BRACKET(STEEL), ALC블록 (150mm):2835473 | 지상 4층 | 3048 | 1600 | 1000 | 새 구성 | 창 | WD812-미들창(스테인리스 스틸) 하부개폐 1000x1600mm | 7464744 | WD812-미들창(스테인리스 스틸) | WD812-미들창(스테인리스 스틸): WD812-미들창(스테인리스 스틸) 하부개폐 1000x1600mm | 2.46752 | WD812-미들창(스테인리스 스틸) 하부개폐 1000x1600mm | 2 | 구속조건 - 레벨: 지상 4층; 씰 높이: 3030 mm; 기타 - 창의개폐비: 50; 헤드 높이: 4630 mm; 호스트 ID: 2820691; 치수 - 벽체 opening 면적: 1.6 m2; 체적: 0.0593112 m3
기본 벽:A2-22-02A-압출스티로폼, BRACKET(STEEL), ALC블록 (150mm):2835473 | 지상 4층 | 3048 | 800 | 1200 | 새 구성 | 창 | WD812-미들창(스테인리스 스틸) 하부개폐 800x1200mm | 7464739 | WD812-미들창(스테인리스 스틸) | WD812-미들창(스테인리스 스틸): WD812-미들창(스테인리스 스틸) 하부개폐 800x1200mm | 1.62992 | WD812-미들창(스테인리스 스틸) 하부개폐 800x1200mm | 2 | 구속조건 - 레벨: 지상 4층; 씰 높이: 1200 mm; 기타 - 창의개폐비: 50; 헤드 높이: 2400 mm; 호스트 ID: 2820691; 치수 - 벽체 opening 면적: 0.96 m2; 체적: 0.0421992 m3
기본 벽:A2-22-02A-압출스티로폼, BRACKET(STEEL), ALC블록 (150mm):2835474 | 지상 4층 | 3048 | 1600 | 1500 | 새 구성 | 창 | WD842-2단 하부 더블 프로젝트 창(스테인리스 스틸)_1500x1600mm | 7468499 | WD842-2단 하부 더블 프로젝트 창(스테인리스 스틸) | WD842-2단 하부 더블 프로젝트 창(스테인리스 스틸): WD842-2단 하부 더블 프로젝트 창(스테인리스 스틸)_1500x1600mm | 3.60783 | WD842-2단 하부 더블 프로젝트 창(스테인리스 스틸)_1500x1600mm | 2 | 구속조건 - 레벨: 지상 4층; 씰 높이: 1000 mm; 기타 - 창의개폐비: 100; 헤드 높이: 2600 mm; 호스트 ID: 5999125; 치수 - 체적: 0.084837 m3
기본 벽:A2-22-02A-압출스티로폼, BRACKET(STEEL), ALC블록 (150mm):2835475:1 | 지상 4층 | 4100 | 14100.6 | 150 |  |  |  |  |  |  |  | A2-22-02A-압출스티로폼, BRACKET(STEEL), ALC블록 (150mm) | 2
기본 벽:A2-26-01A-압출스티로폼, 금속 긴결철물, 금속외장패널 (150mm):2835481 | 지상 5층 | 3048 | 1800 | 2000 | 새 구성 | 창 | WD842-2단 하부 더블 프로젝트 창(스테인리스 스틸)_2000x1800mm | 7468501 | WD842-2단 하부 더블 프로젝트 창(스테인리스 스틸) | WD842-2단 하부 더블 프로젝트 창(스테인리스 스틸): WD842-2단 하부 더블 프로젝트 창(스테인리스 스틸)_2000x1800mm | 5.10973 | WD842-2단 하부 더블 프로젝트 창(스테인리스 스틸)_2000x1800mm | 2 | 구속조건 - 레벨: 지상 5층; 씰 높이: 1000 mm; 기타 - 창의개폐비: 100; 헤드 높이: 2800 mm; 호스트 ID: 2821235; 치수 - 체적: 0.113019 m3
기본 벽:A2-22-02A-압출스티로폼, BRACKET(STEEL), ALC블록 (150mm):2835485 | 지상 5층 | 3048 | 1600 | 1000 | 새 구성 | 창 | WD812-미들창(스테인리스 스틸) 하부개폐 1000x1600mm | 7464744 | WD812-미들창(스테인리스 스틸) | WD812-미들창(스테인리스 스틸): WD812-미들창(스테인리스 스틸) 하부개폐 1000x1600mm | 2.46752 | WD812-미들창(스테인리스 스틸) 하부개폐 1000x1600mm | 2 | 구속조건 - 레벨: 지상 5층; 씰 높이: 3030 mm; 기타 - 창의개폐비: 50; 헤드 높이: 4630 mm; 호스트 ID: 2821193; 치수 - 벽체 opening 면적: 1.6 m2; 체적: 0.0593112 m3
기본 벽:A2-22-02A-압출스티로폼, BRACKET(STEEL), ALC블록 (150mm):2835485 | 지상 5층 | 3048 | 1600 | 1000 | 새 구성 | 창 | WD812-미들창(스테인리스 스틸) 하부개폐 1000x1600mm | 7464744 | WD812-미들창(스테인리스 스틸) | WD812-미들창(스테인리스 스틸): WD812-미들창(스테인리스 스틸) 하부개폐 1000x1600mm | 2.46752 | WD812-미들창(스테인리스 스틸) 하부개폐 1000x1600mm | 2 | 구속조건 - 레벨: 지상 4층; 씰 높이: 3030 mm; 기타 - 창의개폐비: 50; 헤드 높이: 4630 mm; 호스트 ID: 2820691; 치수 - 벽체 opening 면적: 1.6 m2; 체적: 0.0593112 m3
기본 벽:A2-22-02A-압출스티로폼, BRACKET(STEEL), ALC블록 (150mm):2835485 | 지상 5층 | 3048 | 800 | 1200 | 새 구성 | 창 | WD812-미들창(스테인리스 스틸) 하부개폐 800x1200mm | 7464739 | WD812-미들창(스테인리스 스틸) | WD812-미들창(스테인리스 스틸): WD812-미들창(스테인리스 스틸) 하부개폐 800x1200mm | 1.62992 | WD812-미들창(스테인리스 스틸) 하부개폐 800x1200mm | 2 | 구속조건 - 레벨: 지상 5층; 씰 높이: 1200 mm; 기타 - 창의개폐비: 50; 헤드 높이: 2400 mm; 호스트 ID: 2821193; 치수 - 벽체 opening 면적: 0.96 m2; 체적: 0.0421992 m3
기본 벽:A2-22-02A-압출스티로폼, BRACKET(STEEL), ALC블록 (150mm):2835486 | 지상 5층 | 3048 | 1600 | 1500 | 새 구성 | 창 | WD842-2단 하부 더블 프로젝트 창(스테인리스 스틸)_1500x1600mm | 7468499 | WD842-2단 하부 더블 프로젝트 창(스테인리스 스틸) | WD842-2단 하부 더블 프로젝트 창(스테인리스 스틸): WD842-2단 하부 더블 프로젝트 창(스테인리스 스틸)_1500x1600mm | 3.60783 | WD842-2단 하부 더블 프로젝트 창(스테인리스 스틸)_1500x1600mm | 2 | 구속조건 - 레벨: 지상 5층; 씰 높이: 1000 mm; 기타 - 창의개폐비: 100; 헤드 높이: 2600 mm; 호스트 ID: 5999356; 치수 - 체적: 0.084837 m3
기본 벽:A2-22-02A-압출스티로폼, BRACKET(STEEL), ALC블록 (150mm):2835487:1 | 지상 5층 | 4100 | 14100.6 | 150 |  |  |  |  |  |  |  | A2-22-02A-압출스티로폼, BRACKET(STEEL), ALC블록 (150mm) | 2
기본 벽:A2-26-01A-압출스티로폼, 금속 긴결철물, 금속외장패널 (150mm):2835493 | 지상 6층 | 3048 | 1800 | 2000 | 새 구성 | 창 | WD842-2단 하부 더블 프로젝트 창(스테인리스 스틸)_2000x1800mm | 7468501 | WD842-2단 하부 더블 프로젝트 창(스테인리스 스틸) | WD842-2단 하부 더블 프로젝트 창(스테인리스 스틸): WD842-2단 하부 더블 프로젝트 창(스테인리스 스틸)_2000x1800mm | 5.10973 | WD842-2단 하부 더블 프로젝트 창(스테인리스 스틸)_2000x1800mm | 2 | 구속조건 - 레벨: 지상 6층; 씰 높이: 1000 mm; 기타 - 창의개폐비: 100; 헤드 높이: 2800 mm; 호스트 ID: 2821495; 치수 - 체적: 0.113019 m3
기본 벽:A2-22-02A-압출스티로폼, BRACKET(STEEL), ALC블록 (150mm):2835497 | 지상 6층 | 3048 | 1600 | 1000 | 새 구성 | 창 | WD812-미들창(스테인리스 스틸) 하부개폐 1000x1600mm | 7464744 | WD812-미들창(스테인리스 스틸) | WD812-미들창(스테인리스 스틸): WD812-미들창(스테인리스 스틸) 하부개폐 1000x1600mm | 2.46752 | WD812-미들창(스테인리스 스틸) 하부개폐 1000x1600mm | 2 | 구속조건 - 레벨: 지상 6층; 씰 높이: 3030 mm; 기타 - 창의개폐비: 50; 헤드 높이: 4630 mm; 호스트 ID: 2821453; 치수 - 벽체 opening 면적: 1.6 m2; 체적: 0.0593112 m3
기본 벽:A2-22-02A-압출스티로폼, BRACKET(STEEL), ALC블록 (150mm):2835497 | 지상 6층 | 3048 | 1600 | 1000 | 새 구성 | 창 | WD812-미들창(스테인리스 스틸) 하부개폐 1000x1600mm | 7464744 | WD812-미들창(스테인리스 스틸) | WD812-미들창(스테인리스 스틸): WD812-미들창(스테인리스 스틸) 하부개폐 1000x1600mm | 2.46752 | WD812-미들창(스테인리스 스틸) 하부개폐 1000x1600mm | 2 | 구속조건 - 레벨: 지상 5층; 씰 높이: 3030 mm; 기타 - 창의개폐비: 50; 헤드 높이: 4630 mm; 호스트 ID: 2821193; 치수 - 벽체 opening 면적: 1.6 m2; 체적: 0.0593112 m3
기본 벽:A2-22-02A-압출스티로폼, BRACKET(STEEL), ALC블록 (150mm):2835497 | 지상 6층 | 3048 | 800 | 1200 | 새 구성 | 창 | WD812-미들창(스테인리스 스틸) 하부개폐 800x1200mm | 7464739 | WD812-미들창(스테인리스 스틸) | WD812-미들창(스테인리스 스틸): WD812-미들창(스테인리스 스틸) 하부개폐 800x1200mm | 1.62992 | WD812-미들창(스테인리스 스틸) 하부개폐 800x1200mm | 2 | 구속조건 - 레벨: 지상 6층; 씰 높이: 1200 mm; 기타 - 창의개폐비: 50; 헤드 높이: 2400 mm; 호스트 ID: 2821453; 치수 - 벽체 opening 면적: 0.96 m2; 체적: 0.0421992 m3
기본 벽:A2-22-02A-압출스티로폼, BRACKET(STEEL), ALC블록 (150mm):2835498 | 지상 6층 | 3048 | 1600 | 1500 | 새 구성 | 창 | WD842-2단 하부 더블 프로젝트 창(스테인리스 스틸)_1500x1600mm | 7468499 | WD842-2단 하부 더블 프로젝트 창(스테인리스 스틸) | WD842-2단 하부 더블 프로젝트 창(스테인리스 스틸): WD842-2단 하부 더블 프로젝트 창(스테인리스 스틸)_1500x1600mm | 3.60783 | WD842-2단 하부 더블 프로젝트 창(스테인리스 스틸)_1500x1600mm | 2 | 구속조건 - 레벨: 지상 6층; 씰 높이: 1000 mm; 기타 - 창의개폐비: 100; 헤드 높이: 2600 mm; 호스트 ID: 5999548; 치수 - 체적: 0.084837 m3
기본 벽:A2-22-02A-압출스티로폼, BRACKET(STEEL), ALC블록 (150mm):2835499:1 | 지상 6층 | 4100 | 14100.6 | 150 |  |  |  |  |  |  |  | A2-22-02A-압출스티로폼, BRACKET(STEEL), ALC블록 (150mm) | 2
기본 벽:A2-26-01A-압출스티로폼, 금속 긴결철물, 금속외장패널 (150mm):2835505 | 지상 7층 | 3048 | 1800 | 2000 | 새 구성 | 창 | WD842-2단 하부 더블 프로젝트 창(스테인리스 스틸)_2000x1800mm | 7468501 | WD842-2단 하부 더블 프로젝트 창(스테인리스 스틸) | WD842-2단 하부 더블 프로젝트 창(스테인리스 스틸): WD842-2단 하부 더블 프로젝트 창(스테인리스 스틸)_2000x1800mm | 5.10973 | WD842-2단 하부 더블 프로젝트 창(스테인리스 스틸)_2000x1800mm | 2 | 구속조건 - 레벨: 지상 7층; 씰 높이: 1000 mm; 기타 - 창의개폐비: 100; 헤드 높이: 2800 mm; 호스트 ID: 2821691; 치수 - 체적: 0.113019 m3
기본 벽:A2-22-02A-압출스티로폼, BRACKET(STEEL), ALC블록 (150mm):2835509 | 지상 7층 | 3048 | 1600 | 1000 | 새 구성 | 창 | WD812-미들창(스테인리스 스틸) 하부개폐 1000x1600mm | 7464744 | WD812-미들창(스테인리스 스틸) | WD812-미들창(스테인리스 스틸): WD812-미들창(스테인리스 스틸) 하부개폐 1000x1600mm | 2.46752 | WD812-미들창(스테인리스 스틸) 하부개폐 1000x1600mm | 2 | 구속조건 - 레벨: 지상 6층; 씰 높이: 3030 mm; 기타 - 창의개폐비: 50; 헤드 높이: 4630 mm; 호스트 ID: 2821453; 치수 - 벽체 opening 면적: 1.6 m2; 체적: 0.0593112 m3
기본 벽:A2-22-02A-압출스티로폼, BRACKET(STEEL), ALC블록 (150mm):2835509 | 지상 7층 | 3048 | 1600 | 1000 | 새 구성 | 창 | WD812-미들창(스테인리스 스틸) 하부개폐 1000x1600mm | 7464744 | WD812-미들창(스테인리스 스틸) | WD812-미들창(스테인리스 스틸): WD812-미들창(스테인리스 스틸) 하부개폐 1000x1600mm | 2.46752 | WD812-미들창(스테인리스 스틸) 하부개폐 1000x1600mm | 2 | 구속조건 - 레벨: 지상 7층; 씰 높이: 3030 mm; 기타 - 창의개폐비: 50; 헤드 높이: 4630 mm; 호스트 ID: 2821649; 치수 - 벽체 opening 면적: 1.6 m2; 체적: 0.0593112 m3
기본 벽:A2-22-02A-압출스티로폼, BRACKET(STEEL), ALC블록 (150mm):2835509 | 지상 7층 | 3048 | 800 | 1200 | 새 구성 | 창 | WD812-미들창(스테인리스 스틸) 하부개폐 800x1200mm | 7464739 | WD812-미들창(스테인리스 스틸) | WD812-미들창(스테인리스 스틸): WD812-미들창(스테인리스 스틸) 하부개폐 800x1200mm | 1.62992 | WD812-미들창(스테인리스 스틸) 하부개폐 800x1200mm | 2 | 구속조건 - 레벨: 지상 7층; 씰 높이: 1200 mm; 기타 - 창의개폐비: 50; 헤드 높이: 2400 mm; 호스트 ID: 2821649; 치수 - 벽체 opening 면적: 0.96 m2; 체적: 0.0421992 m3
기본 벽:A2-22-02A-압출스티로폼, BRACKET(STEEL), ALC블록 (150mm):2835510 | 지상 7층 | 3048 | 1600 | 1500 | 새 구성 | 창 | WD842-2단 하부 더블 프로젝트 창(스테인리스 스틸)_1500x1600mm | 7468499 | WD842-2단 하부 더블 프로젝트 창(스테인리스 스틸) | WD842-2단 하부 더블 프로젝트 창(스테인리스 스틸): WD842-2단 하부 더블 프로젝트 창(스테인리스 스틸)_1500x1600mm | 3.60783 | WD842-2단 하부 더블 프로젝트 창(스테인리스 스틸)_1500x1600mm | 2 | 구속조건 - 레벨: 지상 7층; 씰 높이: 1000 mm; 기타 - 창의개폐비: 100; 헤드 높이: 2600 mm; 호스트 ID: 5999768; 치수 - 체적: 0.084837 m3
기본 벽:A2-22-02A-압출스티로폼, BRACKET(STEEL), ALC블록 (150mm):2835511:1 | 지상 7층 | 4100 | 14100.6 | 150 |  |  |  |  |  |  |  | A2-22-02A-압출스티로폼, BRACKET(STEEL), ALC블록 (150mm) | 2
기본 벽:A2-26-01A-압출스티로폼, 금속 긴결철물, 금속외장패널 (150mm):2835517 | 지상 8층 | 3048 | 1800 | 2000 | 새 구성 | 창 | WD842-2단 하부 더블 프로젝트 창(스테인리스 스틸)_2000x1800mm | 7468501 | WD842-2단 하부 더블 프로젝트 창(스테인리스 스틸) | WD842-2단 하부 더블 프로젝트 창(스테인리스 스틸): WD842-2단 하부 더블 프로젝트 창(스테인리스 스틸)_2000x1800mm | 5.10973 | WD842-2단 하부 더블 프로젝트 창(스테인리스 스틸)_2000x1800mm | 2 | 구속조건 - 레벨: 지상 8층; 씰 높이: 1000 mm; 기타 - 창의개폐비: 100; 헤드 높이: 2800 mm; 호스트 ID: 2822037; 치수 - 체적: 0.113019 m3
기본 벽:A2-22-02A-압출스티로폼, BRACKET(STEEL), ALC블록 (150mm):2835521 | 지상 8층 | 3048 | 1600 | 1000 | 새 구성 | 창 | WD812-미들창(스테인리스 스틸) 하부개폐 1000x1600mm | 7464744 | WD812-미들창(스테인리스 스틸) | WD812-미들창(스테인리스 스틸): WD812-미들창(스테인리스 스틸) 하부개폐 1000x1600mm | 2.46752 | WD812-미들창(스테인리스 스틸) 하부개폐 1000x1600mm | 2 | 구속조건 - 레벨: 지상 7층; 씰 높이: 3030 mm; 기타 - 창의개폐비: 50; 헤드 높이: 4630 mm; 호스트 ID: 2821649; 치수 - 벽체 opening 면적: 1.6 m2; 체적: 0.0593112 m3
기본 벽:A2-22-02A-압출스티로폼, BRACKET(STEEL), ALC블록 (150mm):2835521 | 지상 8층 | 3048 | 1600 | 1000 | 새 구성 | 창 | WD812-미들창(스테인리스 스틸) 하부개폐 1000x1600mm | 7464744 | WD812-미들창(스테인리스 스틸) | WD812-미들창(스테인리스 스틸): WD812-미들창(스테인리스 스틸) 하부개폐 1000x1600mm | 2.46752 | WD812-미들창(스테인리스 스틸) 하부개폐 1000x1600mm | 2 | 구속조건 - 레벨: 지상 8층; 씰 높이: 3030 mm; 기타 - 창의개폐비: 50; 헤드 높이: 4630 mm; 호스트 ID: 2821995; 치수 - 벽체 opening 면적: 1.6 m2; 체적: 0.0593112 m3
기본 벽:A2-22-02A-압출스티로폼, BRACKET(STEEL), ALC블록 (150mm):2835521 | 지상 8층 | 3048 | 800 | 1200 | 새 구성 | 창 | WD812-미들창(스테인리스 스틸) 하부개폐 800x1200mm | 7464739 | WD812-미들창(스테인리스 스틸) | WD812-미들창(스테인리스 스틸): WD812-미들창(스테인리스 스틸) 하부개폐 800x1200mm | 1.62992 | WD812-미들창(스테인리스 스틸) 하부개폐 800x1200mm | 2 | 구속조건 - 레벨: 지상 8층; 씰 높이: 1200 mm; 기타 - 창의개폐비: 50; 헤드 높이: 2400 mm; 호스트 ID: 2821995; 치수 - 벽체 opening 면적: 0.96 m2; 체적: 0.0421992 m3
기본 벽:A2-22-02A-압출스티로폼, BRACKET(STEEL), ALC블록 (150mm):2835522 | 지상 8층 | 3048 | 1600 | 1500 | 새 구성 | 창 | WD842-2단 하부 더블 프로젝트 창(스테인리스 스틸)_1500x1600mm | 7468499 | WD842-2단 하부 더블 프로젝트 창(스테인리스 스틸) | WD842-2단 하부 더블 프로젝트 창(스테인리스 스틸): WD842-2단 하부 더블 프로젝트 창(스테인리스 스틸)_1500x1600mm | 3.60783 | WD842-2단 하부 더블 프로젝트 창(스테인리스 스틸)_1500x1600mm | 2 | 구속조건 - 레벨: 지상 8층; 씰 높이: 1000 mm; 기타 - 창의개폐비: 100; 헤드 높이: 2600 mm; 호스트 ID: 5999969; 치수 - 체적: 0.084837 m3
기본 벽:A2-22-02A-압출스티로폼, BRACKET(STEEL), ALC블록 (150mm):2835523:1 | 지상 8층 | 4100 | 14100.6 | 150 |  |  |  |  |  |  |  | A2-22-02A-압출스티로폼, BRACKET(STEEL), ALC블록 (150mm) | 2
기본 벽:A2-26-01A-압출스티로폼, 금속 긴결철물, 금속외장패널 (150mm):2835529 | 지상 9층 | 3048 | 1800 | 2000 | 새 구성 | 창 | WD842-2단 하부 더블 프로젝트 창(스테인리스 스틸)_2000x1800mm | 7468501 | WD842-2단 하부 더블 프로젝트 창(스테인리스 스틸) | WD842-2단 하부 더블 프로젝트 창(스테인리스 스틸): WD842-2단 하부 더블 프로젝트 창(스테인리스 스틸)_2000x1800mm | 5.10973 | WD842-2단 하부 더블 프로젝트 창(스테인리스 스틸)_2000x1800mm | 2 | 구속조건 - 레벨: 지상 9층; 씰 높이: 1000 mm; 기타 - 창의개폐비: 100; 헤드 높이: 2800 mm; 호스트 ID: 2822243; 치수 - 체적: 0.113019 m3
기본 벽:A2-22-02A-압출스티로폼, BRACKET(STEEL), ALC블록 (150mm):2835533 | 지상 9층 | 3048 | 1600 | 1000 | 새 구성 | 창 | WD812-미들창(스테인리스 스틸) 하부개폐 1000x1600mm | 7464744 | WD812-미들창(스테인리스 스틸) | WD812-미들창(스테인리스 스틸): WD812-미들창(스테인리스 스틸) 하부개폐 1000x1600mm | 2.46752 | WD812-미들창(스테인리스 스틸) 하부개폐 1000x1600mm | 2 | 구속조건 - 레벨: 지상 8층; 씰 높이: 3030 mm; 기타 - 창의개폐비: 50; 헤드 높이: 4630 mm; 호스트 ID: 2821995; 치수 - 벽체 opening 면적: 1.6 m2; 체적: 0.0593112 m3
기본 벽:A2-22-02A-압출스티로폼, BRACKET(STEEL), ALC블록 (150mm):2835533 | 지상 9층 | 3048 | 1600 | 1000 | 새 구성 | 창 | WD812-미들창(스테인리스 스틸) 하부개폐 1000x1600mm | 7464744 | WD812-미들창(스테인리스 스틸) | WD812-미들창(스테인리스 스틸): WD812-미들창(스테인리스 스틸) 하부개폐 1000x1600mm | 2.46752 | WD812-미들창(스테인리스 스틸) 하부개폐 1000x1600mm | 2 | 구속조건 - 레벨: 지상 9층; 씰 높이: 3415.8 mm; 기타 - 창의개폐비: 50; 헤드 높이: 5015.8 mm; 호스트 ID: 2822201; 치수 - 벽체 opening 면적: 1.6 m2; 체적: 0.0593112 m3
기본 벽:A2-22-02A-압출스티로폼, BRACKET(STEEL), ALC블록 (150mm):2835533 | 지상 9층 | 3048 | 800 | 1200 | 새 구성 | 창 | WD812-미들창(스테인리스 스틸) 하부개폐 800x1200mm | 7464739 | WD812-미들창(스테인리스 스틸) | WD812-미들창(스테인리스 스틸): WD812-미들창(스테인리스 스틸) 하부개폐 800x1200mm | 1.62992 | WD812-미들창(스테인리스 스틸) 하부개폐 800x1200mm | 2 | 구속조건 - 레벨: 지상 9층; 씰 높이: 1200 mm; 기타 - 창의개폐비: 50; 헤드 높이: 2400 mm; 호스트 ID: 2822201; 치수 - 벽체 opening 면적: 0.96 m2; 체적: 0.0421992 m3
기본 벽:A2-22-02A-압출스티로폼, BRACKET(STEEL), ALC블록 (150mm):2835534 | 지상 9층 | 3048 | 1600 | 1500 | 새 구성 | 창 | WD842-2단 하부 더블 프로젝트 창(스테인리스 스틸)_1500x1600mm | 7468499 | WD842-2단 하부 더블 프로젝트 창(스테인리스 스틸) | WD842-2단 하부 더블 프로젝트 창(스테인리스 스틸): WD842-2단 하부 더블 프로젝트 창(스테인리스 스틸)_1500x1600mm | 3.60783 | WD842-2단 하부 더블 프로젝트 창(스테인리스 스틸)_1500x1600mm | 2 | 구속조건 - 레벨: 지상 9층; 씰 높이: 1000 mm; 기타 - 창의개폐비: 100; 헤드 높이: 2600 mm; 호스트 ID: 6000137; 치수 - 체적: 0.084837 m3
기본 벽:A2-22-02A-압출스티로폼, BRACKET(STEEL), ALC블록 (150mm):2835535:1 | 지상 9층 | 4500 | 14100.6 | 150 |  |  |  |  |  |  |  | A2-22-02A-압출스티로폼, BRACKET(STEEL), ALC블록 (150mm) | 2
기본 벽:WA313-화강석잔다듬 벽 (30, 건식50) 80mm:2843567 | 지상 1층 | 384.8 | 11900 | 3520 | 새 구성 | 벽 | CW112-스테인리스 스틸 커튼월 | 7675291 | 커튼월 | 커튼월: CW112-스테인리스 스틸 커튼월 | 41.888 | CW112-스테인리스 스틸 커튼월 | 2 | ID 데이터 - 마크: 6; 해설: SSD; 구속조건 - 매스와 관련됨: no; 룸 경계: yes; 벽 베이스가 부착됩니다.: no; 상단이 부착됩니다.: no; 베이스 구속조건: 지상 1층; 상단 구속조건: 상위 레벨: 지상 2층; 미연결 높이: 3520 mm; 베이스 간격띄우기: 80 mm; 상단 간격띄우기: -1200 mm; 구조 - 구조: no; 구조적 용도: 비교좌장치; 단면형상 정의 - 단면형상: 수직; 수직 그리드 - 각도: 0 deg; 간격띄우기: 0 mm; 맞춤: 시작; 번호: 4; sets with these values: 2; 치수 - 길이: 11900 mm
기본 벽:WA313-화강석잔다듬 벽 (30, 건식50) 80mm:2843567 | 지상 1층 | 384.8 | 9900 | 3520 | 새 구성 | 벽 | CW112-스테인리스 스틸 커튼월 | 7675291 | 커튼월 | 커튼월: CW112-스테인리스 스틸 커튼월 | 34.848 | CW112-스테인리스 스틸 커튼월 | 2 | ID 데이터 - 마크: 8; 해설: SSD; 구속조건 - 매스와 관련됨: no; 룸 경계: yes; 벽 베이스가 부착됩니다.: no; 상단이 부착됩니다.: no; 베이스 구속조건: 지상 1층; 상단 구속조건: 상위 레벨: 지상 2층; 미연결 높이: 3520 mm; 베이스 간격띄우기: 80 mm; 상단 간격띄우기: -1200 mm; 구조 - 구조: no; 구조적 용도: 비교좌장치; 단면형상 정의 - 단면형상: 수직; 수직 그리드 - 각도: 0 deg; 간격띄우기: 0 mm; 맞춤: 시작; 번호: 4; sets with these values: 2; 치수 - 길이: 9900 mm
기본 벽:WA313-화강석잔다듬 벽 (30, 건식50) 80mm:2843567 | 지상 1층 | 384.8 | 9082 | 3520 | 새 구성 | 벽 | CW112-스테인리스 스틸 커튼월 | 7675291 | 커튼월 | 커튼월: CW112-스테인리스 스틸 커튼월 | 31.9686 | CW112-스테인리스 스틸 커튼월 | 2 | ID 데이터 - 마크: 9; 해설: SSD; 구속조건 - 매스와 관련됨: no; 룸 경계: yes; 벽 베이스가 부착됩니다.: no; 상단이 부착됩니다.: no; 베이스 구속조건: 지상 1층; 상단 구속조건: 상위 레벨: 지상 2층; 미연결 높이: 3520 mm; 베이스 간격띄우기: 80 mm; 상단 간격띄우기: -1200 mm; 구조 - 구조: no; 구조적 용도: 비교좌장치; 단면형상 정의 - 단면형상: 수직; 수직 그리드 - 각도: 0 deg; 간격띄우기: 0 mm; 맞춤: 시작; 번호: 4; sets with these values: 2; 치수 - 길이: 9082 mm
기본 벽:A2-22-02A-압출스티로폼, BRACKET(STEEL), ALC블록 (150mm):2890152 | 옥탑층 | 3048 | 1600 | 1000 | 새 구성 | 창 | WD812-미들창(스테인리스 스틸) 하부개폐 1000x1600mm | 7464744 | WD812-미들창(스테인리스 스틸) | WD812-미들창(스테인리스 스틸): WD812-미들창(스테인리스 스틸) 하부개폐 1000x1600mm | 2.46752 | WD812-미들창(스테인리스 스틸) 하부개폐 1000x1600mm | 2 | 구속조건 - 레벨: 지상 10층; 씰 높이: 3919.8 mm; 기타 - 창의개폐비: 50; 헤드 높이: 5519.8 mm; 호스트 ID: 2822387; 치수 - 벽체 opening 면적: 1.6 m2; 체적: 0.0593112 m3
기본 벽:WA313-화강석잔다듬 벽 (30, 건식50) 80mm:2890971 | 옥탑층 | 3048 | 1000 | 1600 | 새 구성 | 창 | WD812-미들창(스테인리스 스틸) 하부개폐 1000x1600mm | 7464744 | WD812-미들창(스테인리스 스틸) | WD812-미들창(스테인리스 스틸): WD812-미들창(스테인리스 스틸) 하부개폐 1000x1600mm | 2.46752 | WD812-미들창(스테인리스 스틸) 하부개폐 1000x1600mm | 2 | 구속조건 - 레벨: 옥탑층; 씰 높이: 1200 mm; 기타 - 창의개폐비: 50; 헤드 높이: 2800 mm; 호스트 ID: 2822841; 치수 - 벽체 opening 면적: 1.6 m2; 체적: 0.0593112 m3
기본 벽:WA313-화강석잔다듬 벽 (30, 건식50) 80mm:2890971 | 옥탑층 | 3048 | 1200 | 800 | 새 구성 | 창 | WD812-미들창(스테인리스 스틸) 하부개폐 800x1200mm | 7464739 | WD812-미들창(스테인리스 스틸) | WD812-미들창(스테인리스 스틸): WD812-미들창(스테인리스 스틸) 하부개폐 800x1200mm | 1.62992 | WD812-미들창(스테인리스 스틸) 하부개폐 800x1200mm | 2 | 구속조건 - 레벨: 옥탑층; 씰 높이: 1200 mm; 기타 - 창의개폐비: 50; 헤드 높이: 2400 mm; 호스트 ID: 2822821; 치수 - 벽체 opening 면적: 0.96 m2; 체적: 0.0421992 m3
기본 벽:WA313-화강석잔다듬 벽 (30, 건식50) 80mm:2891447 | 옥탑층 | 3048 | 1800 | 2100 | 새 구성 | 문 | DR121-쌍여닫이문(철재, 방화문) 1800x2100mm | 7435628 | DR121-쌍여닫이문(철재, 방화문) | DR121-쌍여닫이문(철재, 방화문): DR121-쌍여닫이문(철재, 방화문) 1800x2100mm | 5.32025 | DR121-쌍여닫이문(철재, 방화문) 1800x2100mm | 2 | 구속조건 - 레벨: 옥탑층; 씰 높이: 80 mm; 기타 - 헤드 높이: 2180 mm; 호스트 ID: 2822815; 치수 - 체적: 0.146498 m3; 데이터 - 벽체 opening 면적: 3.78 m2
2 x 기본 벽:WA313-화강석잔다듬 벽 (30, 건식50) 80mm:2891447 | 옥탑층 | 3048 | 1000 | 1600 | 새 구성 | 창 | WD812-미들창(스테인리스 스틸) 하부개폐 1000x1600mm | 7464744 | WD812-미들창(스테인리스 스틸) | WD812-미들창(스테인리스 스틸): WD812-미들창(스테인리스 스틸) 하부개폐 1000x1600mm | 2.46752 | WD812-미들창(스테인리스 스틸) 하부개폐 1000x1600mm | 2 | 구속조건 - 레벨: 옥탑층; 씰 높이: 1200 mm; 기타 - 창의개폐비: 50; 헤드 높이: 2800 mm; 호스트 ID: 2822815; 치수 - 벽체 opening 면적: 1.6 m2; 체적: 0.0593112 m3
기본 벽:WA313-화강석잔다듬 벽 (30, 건식50) 80mm:2891447 | 옥탑층 | 3048 | 1000 | 1600 | 새 구성 | 창 | WD812-미들창(스테인리스 스틸) 하부개폐 1000x1600mm | 7464744 | WD812-미들창(스테인리스 스틸) | WD812-미들창(스테인리스 스틸): WD812-미들창(스테인리스 스틸) 하부개폐 1000x1600mm | 2.46752 | WD812-미들창(스테인리스 스틸) 하부개폐 1000x1600mm | 2 | ID 데이터 - 마크: 58; 구속조건 - 레벨: 옥탑층; 씰 높이: 1200 mm; 기타 - 창의개폐비: 50; 헤드 높이: 2800 mm; 호스트 ID: 2822815; 치수 - 벽체 opening 면적: 1.6 m2; 체적: 0.0593112 m3
기본 벽:WA313-화강석잔다듬 벽 (30, 건식50) 80mm:2891632 | 옥탑층 | 3048 | 1100 | 2100 | 새 구성 | 문 | DR111-외여닫이문(철재, 일반) 1100x2100mm 2 | 8088344 | DR111-외여닫이문(철재, 일반) | DR111-외여닫이문(철재, 일반): DR111-외여닫이문(철재, 일반) 1100x2100mm 2 | 3.66584 | DR111-외여닫이문(철재, 일반) 1100x2100mm 2 | 2 | 구속조건 - 레벨: 옥탑층; 씰 높이: 80 mm; 기타 - 헤드 높이: 2180 mm; 호스트 ID: 2822813; 치수 - 벽체 opening 면적: 2.31 m2; 체적: 0.122657 m3
기본 벽:WA313-화강석잔다듬 벽 (30, 건식50) 80mm:2891632 | 옥탑층 | 3048 | 2100 | 900 | 새 구성 | 문 | DR111-외여닫이문(철재, 일반) 900x2100mm | 7447208 | DR111-외여닫이문(철재, 일반) | DR111-외여닫이문(철재, 일반): DR111-외여닫이문(철재, 일반) 900x2100mm | 3.19384 | DR111-외여닫이문(철재, 일반) 900x2100mm | 2 | 구속조건 - 레벨: 옥탑층; 씰 높이: 80 mm; 기타 - 헤드 높이: 2180 mm; 호스트 ID: 2822813; 치수 - 벽체 opening 면적: 1.89 m2; 체적: 0.108017 m3
기본 벽:WA313-화강석잔다듬 벽 (30, 건식50) 80mm:2891632 | 옥탑층 | 3048 | 1000 | 1600 | 새 구성 | 창 | WD812-미들창(스테인리스 스틸) 하부개폐 1000x1600mm | 7464744 | WD812-미들창(스테인리스 스틸) | WD812-미들창(스테인리스 스틸): WD812-미들창(스테인리스 스틸) 하부개폐 1000x1600mm | 2.46752 | WD812-미들창(스테인리스 스틸) 하부개폐 1000x1600mm | 2 | 구속조건 - 레벨: 옥탑층; 씰 높이: 1200 mm; 기타 - 창의개폐비: 50; 헤드 높이: 2800 mm; 호스트 ID: 2822813; 치수 - 벽체 opening 면적: 1.6 m2; 체적: 0.0593112 m3
기본 벽:A2-26-01A-압출스티로폼, 금속 긴결철물, 금속외장패널 (150mm):2995675 | 지상 4층 | 3048 | 1800 | 2000 | 새 구성 | 창 | WD842-2단 하부 더블 프로젝트 창(스테인리스 스틸)_2000x1800mm | 7468501 | WD842-2단 하부 더블 프로젝트 창(스테인리스 스틸) | WD842-2단 하부 더블 프로젝트 창(스테인리스 스틸): WD842-2단 하부 더블 프로젝트 창(스테인리스 스틸)_2000x1800mm | 5.10973 | WD842-2단 하부 더블 프로젝트 창(스테인리스 스틸)_2000x1800mm | 2 | 구속조건 - 레벨: 지상 4층; 씰 높이: 1000 mm; 기타 - 창의개폐비: 100; 헤드 높이: 2800 mm; 호스트 ID: 2820733; 치수 - 체적: 0.113019 m3
기본 벽:A2-22-02A-압출스티로폼, BRACKET(STEEL), ALC블록 (150mm):2997281 | 지상 5층 | 454.8 | 27982 | 2000 | 새 구성 | 벽 | CW112-스테인리스 스틸 커튼월 | 7675291 | 커튼월 | 커튼월: CW112-스테인리스 스틸 커튼월 | 55.964 | CW112-스테인리스 스틸 커튼월 | 2 | ID 데이터 - 마크: 29; 해설: AW; 구속조건 - 매스와 관련됨: no; 룸 경계: yes; 벽 베이스가 부착됩니다.: no; 상단이 부착됩니다.: no; 베이스 구속조건: 지상 5층; 상단 구속조건: 상위 레벨: 지상 6층; 미연결 높이: 2000 mm; 베이스 간격띄우기: 600 mm; 상단 간격띄우기: -1500 mm; 구조 - 구조: no; 구조적 용도: 비교좌장치; 단면형상 정의 - 단면형상: 수직; 수직 그리드 - 각도: 0 deg; 간격띄우기: 0 mm; 맞춤: 시작; 번호: 4; sets with these values: 2; 치수 - 길이: 27982 mm
기본 벽:A2-22-02A-압출스티로폼, BRACKET(STEEL), ALC블록 (150mm):2998521:1 | 지상 3층 | 4100 | 14100.6 | 150 |  |  |  |  |  |  |  | A2-22-02A-압출스티로폼, BRACKET(STEEL), ALC블록 (150mm) | 2
기본 벽:WA211-시멘트벽돌(일반) 벽 (0.5B) 90mm:3165333 | 지상 1층 | 394.8 | 11792 | 3520 | 새 구성 | 벽 | WA313-화강석잔다듬 벽 (30, 건식50) 80mm | 7431676 | 기본 벽 | 기본 벽: WA313-화강석잔다듬 벽 (30, 건식50) 80mm | 41.5078 | WA313-화강석잔다듬 벽 (30, 건식50) 80mm | 2 | ID 데이터 - 마크: 17; 해설: SSD; 구속조건 - 매스와 관련됨: no; 룸 경계: yes; 벽 베이스가 부착됩니다.: no; 상단이 부착됩니다.: no; 베이스 구속조건: 지상 1층; 상단 구속조건: 상위 레벨: 지상 2층; 미연결 높이: 3520 mm; 베이스 간격띄우기: 80 mm; 상단 간격띄우기: -1200 mm; 베이스 확장 거리: 0 mm; 상단 확장 거리: 0 mm; 위치선: 마감면:외부; 구조 - 구조: no; 구조적 용도: 비교좌장치; 단면형상 정의 - 단면형상: 수직; 치수 - 길이: 11792 mm; 체적: 3.32063 m3
기본 벽:WA211-시멘트벽돌(일반) 벽 (0.5B) 90mm:3166408 | 지상 1층 | 394.8 | 6599.98 | 3520 | 새 구성 | 벽 | CW112-스테인리스 스틸 커튼월 | 7675291 | 커튼월 | 커튼월: CW112-스테인리스 스틸 커튼월 | 23.2319 | CW112-스테인리스 스틸 커튼월 | 2 | ID 데이터 - 마크: 23; 해설: SSD; 구속조건 - 매스와 관련됨: no; 룸 경계: yes; 벽 베이스가 부착됩니다.: no; 상단이 부착됩니다.: no; 베이스 구속조건: 지상 1층; 상단 구속조건: 상위 레벨: 지상 2층; 미연결 높이: 3520 mm; 베이스 간격띄우기: 80 mm; 상단 간격띄우기: -1200 mm; 구조 - 구조: no; 구조적 용도: 비교좌장치; 단면형상 정의 - 단면형상: 수직; 수직 그리드 - 각도: 0 deg; 간격띄우기: 0 mm; 맞춤: 시작; 번호: 4; sets with these values: 2; 치수 - 길이: 6599.98 mm
기본 벽:WA211-시멘트벽돌(일반) 벽 (0.5B) 90mm:3166491 | 지상 1층 | 394.8 | 2593.15 | 3520 | 새 구성 | 벽 | CW112-스테인리스 스틸 커튼월 | 7675291 | 커튼월 | 커튼월: CW112-스테인리스 스틸 커튼월 | 9.1279 | CW112-스테인리스 스틸 커튼월 | 2 | ID 데이터 - 마크: 24; 해설: SSD; 구속조건 - 매스와 관련됨: no; 룸 경계: yes; 벽 베이스가 부착됩니다.: no; 상단이 부착됩니다.: no; 베이스 구속조건: 지상 1층; 상단 구속조건: 상위 레벨: 지상 2층; 미연결 높이: 3520 mm; 베이스 간격띄우기: 80 mm; 상단 간격띄우기: -1200 mm; 구조 - 구조: no; 구조적 용도: 비교좌장치; 단면형상 정의 - 단면형상: 수직; 수직 그리드 - 각도: 0 deg; 간격띄우기: 0 mm; 맞춤: 시작; 번호: 4; sets with these values: 2; 치수 - 길이: 2693.15 mm
기본 벽:WA211-시멘트벽돌(일반) 벽 (0.5B) 90mm:3166618:1 | 지상 1층 |  |  |  |  |  |  |  |  |  |  | WA211-시멘트벽돌(일반) 벽 (0.5B) 90mm | 2
기본 벽:WA211-시멘트벽돌(일반) 벽 (0.5B) 90mm:3166618 | 지상 1층 | 394.8 | 10700 | 3520 | 새 구성 | 벽 | CW112-스테인리스 스틸 커튼월 | 7675291 | 커튼월 | 커튼월: CW112-스테인리스 스틸 커튼월 | 37.664 | CW112-스테인리스 스틸 커튼월 | 2 | ID 데이터 - 마크: 20; 해설: SSD; 구속조건 - 매스와 관련됨: no; 룸 경계: yes; 벽 베이스가 부착됩니다.: no; 상단이 부착됩니다.: no; 베이스 구속조건: 지상 1층; 상단 구속조건: 상위 레벨: 지상 2층; 미연결 높이: 3520 mm; 베이스 간격띄우기: 80 mm; 상단 간격띄우기: -1200 mm; 구조 - 구조: no; 구조적 용도: 비교좌장치; 단면형상 정의 - 단면형상: 수직; 수직 그리드 - 각도: 0 deg; 간격띄우기: 0 mm; 맞춤: 시작; 번호: 4; sets with these values: 2; 치수 - 길이: 10700 mm
기본 벽:WA211-시멘트벽돌(일반) 벽 (0.5B) 90mm:3166717 | 지상 1층 | 394.8 | 3520 | 10700 | 새 구성 | 벽 | CW112-스테인리스 스틸 커튼월 | 7675291 | 커튼월 | 커튼월: CW112-스테인리스 스틸 커튼월 | 37.664 | CW112-스테인리스 스틸 커튼월 | 2 | ID 데이터 - 마크: 21; 해설: SSD; 구속조건 - 매스와 관련됨: no; 룸 경계: yes; 벽 베이스가 부착됩니다.: no; 상단이 부착됩니다.: no; 베이스 구속조건: 지상 1층; 상단 구속조건: 상위 레벨: 지상 2층; 미연결 높이: 3520 mm; 베이스 간격띄우기: 80 mm; 상단 간격띄우기: -1200 mm; 구조 - 구조: no; 구조적 용도: 비교좌장치; 단면형상 정의 - 단면형상: 수직; 수직 그리드 - 각도: 0 deg; 간격띄우기: 0 mm; 맞춤: 시작; 번호: 4; sets with these values: 2; 치수 - 길이: 10700 mm
기본 벽:WA211-시멘트벽돌(일반) 벽 (0.5B) 90mm:3167103 | 지상 1층 | 394.8 | 3520 | 2500.02 | 새 구성 | 벽 | CW112-스테인리스 스틸 커튼월 | 7675291 | 커튼월 | 커튼월: CW112-스테인리스 스틸 커튼월 | 8.80006 | CW112-스테인리스 스틸 커튼월 | 2 | ID 데이터 - 마크: 15; 해설: SSD; 구속조건 - 매스와 관련됨: no; 룸 경계: yes; 벽 베이스가 부착됩니다.: no; 상단이 부착됩니다.: no; 베이스 구속조건: 지상 1층; 상단 구속조건: 상위 레벨: 지상 2층; 미연결 높이: 3520 mm; 베이스 간격띄우기: 80 mm; 상단 간격띄우기: -1200 mm; 구조 - 구조: no; 구조적 용도: 비교좌장치; 단면형상 정의 - 단면형상: 수직; 수직 그리드 - 각도: 0 deg; 간격띄우기: 0 mm; 맞춤: 시작; 번호: 4; sets with these values: 2; 치수 - 길이: 2590.02 mm
기본 벽:WA211-시멘트벽돌(일반) 벽 (0.5B) 90mm:3167156 | 지상 1층 | 394.8 | 3520 | 2545.02 | 새 구성 | 벽 | CW112-스테인리스 스틸 커튼월 | 7675291 | 커튼월 | 커튼월: CW112-스테인리스 스틸 커튼월 | 8.95846 | CW112-스테인리스 스틸 커튼월 | 2 | ID 데이터 - 마크: 7; 해설: SSD; 구속조건 - 매스와 관련됨: no; 룸 경계: yes; 벽 베이스가 부착됩니다.: no; 상단이 부착됩니다.: no; 베이스 구속조건: 지상 1층; 상단 구속조건: 상위 레벨: 지상 2층; 미연결 높이: 3520 mm; 베이스 간격띄우기: 80 mm; 상단 간격띄우기: -1200 mm; 구조 - 구조: no; 구조적 용도: 비교좌장치; 단면형상 정의 - 단면형상: 수직; 수직 그리드 - 각도: 0 deg; 간격띄우기: 0 mm; 맞춤: 시작; 번호: 4; sets with these values: 2; 치수 - 길이: 2590.02 mm
기본 벽:WA211-시멘트벽돌(일반) 벽 (0.5B) 90mm:3167385 | 지상 1층 | 394.8 | 2500 | 4020 | 새 구성 | 벽 | CW112-스테인리스 스틸 커튼월 | 7675291 | 커튼월 | 커튼월: CW112-스테인리스 스틸 커튼월 | 10.05 | CW112-스테인리스 스틸 커튼월 | 2 | ID 데이터 - 마크: 15; 해설: SSD; 구속조건 - 매스와 관련됨: no; 룸 경계: yes; 벽 베이스가 부착됩니다.: no; 상단이 부착됩니다.: no; 베이스 구속조건: 지상 1층; 상단 구속조건: 상위 레벨: 지상 2층; 미연결 높이: 4020 mm; 베이스 간격띄우기: -420 mm; 상단 간격띄우기: -1200 mm; 구조 - 구조: no; 구조적 용도: 비교좌장치; 단면형상 정의 - 단면형상: 수직; 수직 그리드 - 각도: 0 deg; 간격띄우기: 0 mm; 맞춤: 시작; 번호: 4; sets with these values: 2; 치수 - 길이: 2600 mm
기본 벽:WA211-시멘트벽돌(일반) 벽 (0.5B) 90mm:3167450 | 지상 1층 | 394.8 | 6492.47 | 3520 | 새 구성 | 벽 | CW112-스테인리스 스틸 커튼월 | 7675291 | 커튼월 | 커튼월: CW112-스테인리스 스틸 커튼월 | 22.8535 | CW112-스테인리스 스틸 커튼월 | 2 | ID 데이터 - 마크: 15; 해설: SSD; 구속조건 - 매스와 관련됨: no; 룸 경계: yes; 벽 베이스가 부착됩니다.: no; 상단이 부착됩니다.: no; 베이스 구속조건: 지상 1층; 상단 구속조건: 상위 레벨: 지상 2층; 미연결 높이: 3520 mm; 베이스 간격띄우기: 80 mm; 상단 간격띄우기: -1200 mm; 구조 - 구조: no; 구조적 용도: 비교좌장치; 단면형상 정의 - 단면형상: 수직; 수직 그리드 - 각도: 0 deg; 간격띄우기: 0 mm; 맞춤: 시작; 번호: 4; sets with these values: 2; 치수 - 길이: 6568.72 mm
기본 벽:WA313-화강석잔다듬 벽 (30, 건식50) 80mm:3181684 | 지상 2층 | 384.8 | 2020 | 1300.01 | 새 구성 | 벽 | CW112-스테인리스 스틸 커튼월 | 7675291 | 커튼월 | 커튼월: CW112-스테인리스 스틸 커튼월 | 2.62602 | CW112-스테인리스 스틸 커튼월 | 2 | ID 데이터 - 마크: 13; 해설: SSD; 구속조건 - 매스와 관련됨: no; 룸 경계: yes; 벽 베이스가 부착됩니다.: no; 상단이 부착됩니다.: no; 베이스 구속조건: 지상 2층; 상단 구속조건: 상위 레벨: 지상 3층; 미연결 높이: 2020 mm; 베이스 간격띄우기: 80 mm; 상단 간격띄우기: -2400 mm; 구조 - 구조: no; 구조적 용도: 비교좌장치; 단면형상 정의 - 단면형상: 수직; 수직 그리드 - 각도: 0 deg; 간격띄우기: 0 mm; 맞춤: 시작; 번호: 4; sets with these values: 2; 치수 - 길이: 1300.01 mm
기본 벽:WA313-화강석잔다듬 벽 (30, 건식50) 80mm:3181709 | 지상 3층 | 384.8 | 2020 | 1250 | 새 구성 | 벽 | CW112-스테인리스 스틸 커튼월 | 7675291 | 커튼월 | 커튼월: CW112-스테인리스 스틸 커튼월 | 2.525 | CW112-스테인리스 스틸 커튼월 | 2 | ID 데이터 - 마크: 13; 해설: SSD; 구속조건 - 매스와 관련됨: no; 룸 경계: yes; 벽 베이스가 부착됩니다.: no; 상단이 부착됩니다.: no; 베이스 구속조건: 지상 3층; 상단 구속조건: 상위 레벨: 지상 4층; 미연결 높이: 2020 mm; 베이스 간격띄우기: 80 mm; 상단 간격띄우기: -2000 mm; 구조 - 구조: no; 구조적 용도: 비교좌장치; 단면형상 정의 - 단면형상: 수직; 수직 그리드 - 각도: 0 deg; 간격띄우기: 0 mm; 맞춤: 시작; 번호: 4; sets with these values: 2; 치수 - 길이: 1250 mm
기본 벽:WA313-화강석잔다듬 벽 (30, 건식50) 80mm:3181730 | 지상 4층 | 384.8 |  |  | 새 구성 | 벽 | CW112-스테인리스 스틸 커튼월 | 7675291 | 커튼월 | 커튼월: CW112-스테인리스 스틸 커튼월 | 0.70275 | CW112-스테인리스 스틸 커튼월 | 2 | ID 데이터 - 마크: 13; 해설: SSD; 구속조건 - 매스와 관련됨: no; 룸 경계: yes; 벽 베이스가 부착됩니다.: no; 상단이 부착됩니다.: no; 베이스 구속조건: 지상 4층; 상단 구속조건: 상위 레벨: 지상 5층; 미연결 높이: 2020 mm; 베이스 간격띄우기: 80 mm; 상단 간격띄우기: -2000 mm; 구조 - 구조: no; 구조적 용도: 비교좌장치; 단면형상 정의 - 단면형상: 수직; 수직 그리드 - 각도: 0 deg; 간격띄우기: 0 mm; 맞춤: 시작; 번호: 4; sets with these values: 2; 치수 - 길이: 1250 mm; BaseQuantities - Area: 0.70275 m2
기본 벽:WA313-화강석잔다듬 벽 (30, 건식50) 80mm:3181730 | 지상 4층 | 3048 | 1970 | 925 | 새 구성 | 문 | DR111-외여닫이문(유리, 일반, 양개) 925x1970mm 2 | 7694949 | DR111-외여닫이문(철재, 일반, 양개) | DR111-외여닫이문(철재, 일반, 양개): DR111-외여닫이문(유리, 일반, 양개) 925x1970mm 2 | 2.89387 | DR111-외여닫이문(유리, 일반, 양개) 925x1970mm 2 | 2 | ID 데이터 - 마크: 25XXX; 구속조건 - 레벨: 지상 4층; 씰 높이: 80 mm; 기타 - 헤드 높이: 2050 mm; 호스트 ID: 2820729; 치수 - 벽체 opening 면적: 1.82225 m2; 체적: 0.0548052 m3
기본 벽:WA313-화강석잔다듬 벽 (30, 건식50) 80mm:3181751 | 지상 5층 | 384.8 |  |  | 새 구성 | 벽 | CW112-스테인리스 스틸 커튼월 | 7675291 | 커튼월 | 커튼월: CW112-스테인리스 스틸 커튼월 | 0.803768 | CW112-스테인리스 스틸 커튼월 | 2 | ID 데이터 - 마크: 13; 해설: SSD; 구속조건 - 매스와 관련됨: no; 룸 경계: yes; 벽 베이스가 부착됩니다.: no; 상단이 부착됩니다.: no; 베이스 구속조건: 지상 5층; 상단 구속조건: 상위 레벨: 지상 6층; 미연결 높이: 2020 mm; 베이스 간격띄우기: 80 mm; 상단 간격띄우기: -2000 mm; 구조 - 구조: no; 구조적 용도: 비교좌장치; 단면형상 정의 - 단면형상: 수직; 수직 그리드 - 각도: 0 deg; 간격띄우기: 0 mm; 맞춤: 시작; 번호: 4; sets with these values: 2; 치수 - 길이: 1300.01 mm; BaseQuantities - Area: 0.803768 m2
기본 벽:WA313-화강석잔다듬 벽 (30, 건식50) 80mm:3181751 | 지상 5층 | 3048 | 1970 | 925 | 새 구성 | 문 | DR111-외여닫이문(유리, 일반, 양개) 925x1970mm 2 | 7694949 | DR111-외여닫이문(철재, 일반, 양개) | DR111-외여닫이문(철재, 일반, 양개): DR111-외여닫이문(유리, 일반, 양개) 925x1970mm 2 | 2.89387 | DR111-외여닫이문(유리, 일반, 양개) 925x1970mm 2 | 2 | ID 데이터 - 마크: 25YYY; 구속조건 - 레벨: 지상 5층; 씰 높이: 80 mm; 기타 - 헤드 높이: 2050 mm; 호스트 ID: 2821231; 치수 - 벽체 opening 면적: 1.82225 m2; 체적: 0.0548052 m3
기본 벽:WA313-화강석잔다듬 벽 (30, 건식50) 80mm:3181772 | 지상 6층 | 384.8 |  |  | 새 구성 | 벽 | CW112-스테인리스 스틸 커튼월 | 7675291 | 커튼월 | 커튼월: CW112-스테인리스 스틸 커튼월 | 0.803768 | CW112-스테인리스 스틸 커튼월 | 2 | ID 데이터 - 마크: 13; 해설: SSD; 구속조건 - 매스와 관련됨: no; 룸 경계: yes; 벽 베이스가 부착됩니다.: no; 상단이 부착됩니다.: no; 베이스 구속조건: 지상 6층; 상단 구속조건: 상위 레벨: 지상 7층; 미연결 높이: 2020 mm; 베이스 간격띄우기: 80 mm; 상단 간격띄우기: -2000 mm; 구조 - 구조: no; 구조적 용도: 비교좌장치; 단면형상 정의 - 단면형상: 수직; 수직 그리드 - 각도: 0 deg; 간격띄우기: 0 mm; 맞춤: 시작; 번호: 4; sets with these values: 2; 치수 - 길이: 1300.01 mm; BaseQuantities - Area: 0.803768 m2
기본 벽:WA313-화강석잔다듬 벽 (30, 건식50) 80mm:3181772 | 지상 6층 | 3048 | 1970 | 925 | 새 구성 | 문 | DR111-외여닫이문(유리, 일반, 양개) 925x1970mm 2 | 7694949 | DR111-외여닫이문(철재, 일반, 양개) | DR111-외여닫이문(철재, 일반, 양개): DR111-외여닫이문(유리, 일반, 양개) 925x1970mm 2 | 2.89387 | DR111-외여닫이문(유리, 일반, 양개) 925x1970mm 2 | 2 | ID 데이터 - 마크: 25ZZZ; 구속조건 - 레벨: 지상 6층; 씰 높이: 80 mm; 기타 - 헤드 높이: 2050 mm; 호스트 ID: 2821491; 치수 - 벽체 opening 면적: 1.82225 m2; 체적: 0.0548052 m3
기본 벽:WA313-화강석잔다듬 벽 (30, 건식50) 80mm:3181793 | 지상 7층 | 384.8 |  |  | 새 구성 | 벽 | CW112-스테인리스 스틸 커튼월 | 7675291 | 커튼월 | 커튼월: CW112-스테인리스 스틸 커튼월 | 0.803768 | CW112-스테인리스 스틸 커튼월 | 2 | ID 데이터 - 마크: 13; 해설: SSD; 구속조건 - 매스와 관련됨: no; 룸 경계: yes; 벽 베이스가 부착됩니다.: no; 상단이 부착됩니다.: no; 베이스 구속조건: 지상 7층; 상단 구속조건: 상위 레벨: 지상 8층; 미연결 높이: 2020 mm; 베이스 간격띄우기: 80 mm; 상단 간격띄우기: -2000 mm; 구조 - 구조: no; 구조적 용도: 비교좌장치; 단면형상 정의 - 단면형상: 수직; 수직 그리드 - 각도: 0 deg; 간격띄우기: 0 mm; 맞춤: 시작; 번호: 4; sets with these values: 2; 치수 - 길이: 1300.01 mm; BaseQuantities - Area: 0.803768 m2
기본 벽:WA313-화강석잔다듬 벽 (30, 건식50) 80mm:3181793 | 지상 7층 | 3048 | 1970 | 925 | 새 구성 | 문 | DR111-외여닫이문(유리, 일반, 양개) 925x1970mm 2 | 7694949 | DR111-외여닫이문(철재, 일반, 양개) | DR111-외여닫이문(철재, 일반, 양개): DR111-외여닫이문(유리, 일반, 양개) 925x1970mm 2 | 2.89387 | DR111-외여닫이문(유리, 일반, 양개) 925x1970mm 2 | 2 | ID 데이터 - 마크: 25AAAA; 구속조건 - 레벨: 지상 7층; 씰 높이: 80 mm; 기타 - 헤드 높이: 2050 mm; 호스트 ID: 2821687; 치수 - 벽체 opening 면적: 1.82225 m2; 체적: 0.0548052 m3
기본 벽:WA313-화강석잔다듬 벽 (30, 건식50) 80mm:3181814 | 지상 8층 | 384.8 |  |  | 새 구성 | 벽 | CW112-스테인리스 스틸 커튼월 | 7675291 | 커튼월 | 커튼월: CW112-스테인리스 스틸 커튼월 | 0.803768 | CW112-스테인리스 스틸 커튼월 | 2 | ID 데이터 - 마크: 13; 해설: SSD; 구속조건 - 매스와 관련됨: no; 룸 경계: yes; 벽 베이스가 부착됩니다.: no; 상단이 부착됩니다.: no; 베이스 구속조건: 지상 8층; 상단 구속조건: 상위 레벨: 지상 9층; 미연결 높이: 2020 mm; 베이스 간격띄우기: 80 mm; 상단 간격띄우기: -2000 mm; 구조 - 구조: no; 구조적 용도: 비교좌장치; 단면형상 정의 - 단면형상: 수직; 수직 그리드 - 각도: 0 deg; 간격띄우기: 0 mm; 맞춤: 시작; 번호: 4; sets with these values: 2; 치수 - 길이: 1300.01 mm; BaseQuantities - Area: 0.803768 m2
기본 벽:WA313-화강석잔다듬 벽 (30, 건식50) 80mm:3181814 | 지상 8층 | 3048 | 1970 | 925 | 새 구성 | 문 | DR111-외여닫이문(유리, 일반, 양개) 925x1970mm 2 | 7694949 | DR111-외여닫이문(철재, 일반, 양개) | DR111-외여닫이문(철재, 일반, 양개): DR111-외여닫이문(유리, 일반, 양개) 925x1970mm 2 | 2.89387 | DR111-외여닫이문(유리, 일반, 양개) 925x1970mm 2 | 2 | ID 데이터 - 마크: 25BBBB; 구속조건 - 레벨: 지상 8층; 씰 높이: 80 mm; 기타 - 헤드 높이: 2050 mm; 호스트 ID: 2822033; 치수 - 벽체 opening 면적: 1.82225 m2; 체적: 0.0548052 m3
기본 벽:WA313-화강석잔다듬 벽 (30, 건식50) 80mm:3181835 | 지상 9층 | 384.8 |  |  | 새 구성 | 벽 | CW112-스테인리스 스틸 커튼월 | 7675291 | 커튼월 | 커튼월: CW112-스테인리스 스틸 커튼월 | 0.803768 | CW112-스테인리스 스틸 커튼월 | 2 | ID 데이터 - 마크: 13; 해설: SSD; 구속조건 - 매스와 관련됨: no; 룸 경계: yes; 벽 베이스가 부착됩니다.: no; 상단이 부착됩니다.: no; 베이스 구속조건: 지상 9층; 상단 구속조건: 상위 레벨: 지상 10층; 미연결 높이: 2020 mm; 베이스 간격띄우기: 80 mm; 상단 간격띄우기: -2400 mm; 구조 - 구조: no; 구조적 용도: 비교좌장치; 단면형상 정의 - 단면형상: 수직; 수직 그리드 - 각도: 0 deg; 간격띄우기: 0 mm; 맞춤: 시작; 번호: 4; sets with these values: 2; 치수 - 길이: 1300.01 mm; BaseQuantities - Area: 0.803768 m2
기본 벽:WA313-화강석잔다듬 벽 (30, 건식50) 80mm:3181835 | 지상 9층 | 3048 | 1970 | 925 | 새 구성 | 문 | DR111-외여닫이문(유리, 일반, 양개) 925x1970mm 2 | 7694949 | DR111-외여닫이문(철재, 일반, 양개) | DR111-외여닫이문(철재, 일반, 양개): DR111-외여닫이문(유리, 일반, 양개) 925x1970mm 2 | 2.89387 | DR111-외여닫이문(유리, 일반, 양개) 925x1970mm 2 | 2 | ID 데이터 - 마크: 25CCCC; 구속조건 - 레벨: 지상 9층; 씰 높이: 80 mm; 기타 - 헤드 높이: 2050 mm; 호스트 ID: 2822239; 치수 - 벽체 opening 면적: 1.82225 m2; 체적: 0.0548052 m3
기본 벽:A2-26-01A-압출스티로폼, 금속 긴결철물, 금속외장패널 (150mm):5231647 | 지상 3층 | 454.8 | 2099.37 | 2620 | 새 구성 | 벽 | CW112-스테인리스 스틸 커튼월 | 7675291 | 커튼월 | 커튼월: CW112-스테인리스 스틸 커튼월 | 5.50034 | CW112-스테인리스 스틸 커튼월 | 2 | ID 데이터 - 마크: 22; 해설: AW; 구속조건 - 매스와 관련됨: no; 룸 경계: yes; 벽 베이스가 부착됩니다.: no; 상단이 부착됩니다.: no; 베이스 구속조건: 지상 3층; 상단 구속조건: 상위 레벨: 지상 4층; 미연결 높이: 2620 mm; 베이스 간격띄우기: 80 mm; 상단 간격띄우기: -1400 mm; 구조 - 구조: no; 구조적 용도: 비교좌장치; 단면형상 정의 - 단면형상: 수직; 수직 그리드 - 각도: 0 deg; 간격띄우기: 0 mm; 맞춤: 시작; 번호: 4; sets with these values: 2; 치수 - 길이: 2099.37 mm
기본 벽:A2-26-01A-압출스티로폼, 금속 긴결철물, 금속외장패널 (150mm):5231648 | 지상 3층 | 454.8 | 35400 | 2620 | 새 구성 | 벽 | CW112-스테인리스 스틸 커튼월 | 7675291 | 커튼월 | 커튼월: CW112-스테인리스 스틸 커튼월 | 92.748 | CW112-스테인리스 스틸 커튼월 | 2 | ID 데이터 - 마크: 23; 해설: AW; 구속조건 - 매스와 관련됨: no; 룸 경계: yes; 벽 베이스가 부착됩니다.: no; 상단이 부착됩니다.: no; 베이스 구속조건: 지상 3층; 상단 구속조건: 상위 레벨: 지상 4층; 미연결 높이: 2620 mm; 베이스 간격띄우기: 80 mm; 상단 간격띄우기: -1400 mm; 구조 - 구조: no; 구조적 용도: 비교좌장치; 단면형상 정의 - 단면형상: 수직; 수직 그리드 - 각도: 0 deg; 간격띄우기: 0 mm; 맞춤: 시작; 번호: 4; sets with these values: 2; 치수 - 길이: 35400 mm
기본 벽:WA111-철근콘크리트구조 벽 200mm_CW1:5256435:1 | 지상 3층 |  |  |  |  |  |  |  |  |  |  | WA111-철근콘크리트구조 벽 200mm_CW1 | 2
기본 벽:WA211-시멘트벽돌(일반) 벽 (0.5B) 90mm:5343816 | 지하2층 | 394.8 | 2500 | 2390 | 새 구성 | 벽 | CW112-스테인리스 스틸 커튼월 | 7675291 | 커튼월 | 커튼월: CW112-스테인리스 스틸 커튼월 | 5.975 | CW112-스테인리스 스틸 커튼월 | 2 | ID 데이터 - 마크: 1; 해설: SSD; 구속조건 - 매스와 관련됨: no; 룸 경계: yes; 벽 베이스가 부착됩니다.: no; 상단이 부착됩니다.: no; 베이스 구속조건: 지하2층; 상단 구속조건: 상위 레벨: 지하1층; 미연결 높이: 2390 mm; 베이스 간격띄우기: 200 mm; 상단 간격띄우기: -1410 mm; 구조 - 구조: no; 구조적 용도: 비교좌장치; 단면형상 정의 - 단면형상: 수직; 수직 그리드 - 각도: 0 deg; 간격띄우기: 0 mm; 맞춤: 시작; 번호: 4; sets with these values: 2; 치수 - 길이: 2500 mm
기본 벽:WA211-시멘트벽돌(일반) 벽 (0.5B) 90mm:5343955 | 지하2층 | 394.8 | 2390 | 2600 | 새 구성 | 벽 | CW112-스테인리스 스틸 커튼월 | 7675291 | 커튼월 | 커튼월: CW112-스테인리스 스틸 커튼월 | 6.214 | CW112-스테인리스 스틸 커튼월 | 2 | ID 데이터 - 마크: 1; 해설: SSD; 구속조건 - 매스와 관련됨: no; 룸 경계: yes; 벽 베이스가 부착됩니다.: no; 상단이 부착됩니다.: no; 베이스 구속조건: 지하2층; 상단 구속조건: 상위 레벨: 지하1층; 미연결 높이: 2390 mm; 베이스 간격띄우기: 200 mm; 상단 간격띄우기: -1410 mm; 구조 - 구조: no; 구조적 용도: 비교좌장치; 단면형상 정의 - 단면형상: 수직; 수직 그리드 - 각도: 0 deg; 간격띄우기: 0 mm; 맞춤: 시작; 번호: 4; sets with these values: 2; 치수 - 길이: 2600 mm
기본 벽:WA211-시멘트벽돌(일반) 벽 (0.5B) 90mm:5344479 | 지하1층 | 394.8 | 2496.09 | 2600 | 새 구성 | 벽 | CW112-스테인리스 스틸 커튼월 | 7675291 | 커튼월 | 커튼월: CW112-스테인리스 스틸 커튼월 | 6.48984 | CW112-스테인리스 스틸 커튼월 | 2 | ID 데이터 - 마크: 1; 해설: SSD; 구속조건 - 매스와 관련됨: no; 룸 경계: yes; 벽 베이스가 부착됩니다.: no; 상단이 부착됩니다.: no; 베이스 구속조건: 지하1층; 상단 구속조건: 상위 레벨: GL; 미연결 높이: 2600 mm; 베이스 간격띄우기: 200 mm; 상단 간격띄우기: -3150 mm; 구조 - 구조: no; 구조적 용도: 비교좌장치; 단면형상 정의 - 단면형상: 수직; 수직 그리드 - 각도: 0 deg; 간격띄우기: 0 mm; 맞춤: 시작; 번호: 4; sets with these values: 2; 치수 - 길이: 2496.09 mm
기본 벽:WA211-시멘트벽돌(일반) 벽 (0.5B) 90mm:5344540 | 지하1층 | 394.8 | 5050 | 2600 | 새 구성 | 벽 | CW112-스테인리스 스틸 커튼월 | 7675291 | 커튼월 | 커튼월: CW112-스테인리스 스틸 커튼월 | 13.13 | CW112-스테인리스 스틸 커튼월 | 2 | ID 데이터 - 마크: 1; 해설: SSD; 구속조건 - 매스와 관련됨: no; 룸 경계: yes; 벽 베이스가 부착됩니다.: no; 상단이 부착됩니다.: no; 베이스 구속조건: 지하1층; 상단 구속조건: 상위 레벨: GL; 미연결 높이: 2600 mm; 베이스 간격띄우기: 200 mm; 상단 간격띄우기: -3150 mm; 구조 - 구조: no; 구조적 용도: 비교좌장치; 단면형상 정의 - 단면형상: 수직; 수직 그리드 - 각도: 0 deg; 간격띄우기: 0 mm; 맞춤: 시작; 번호: 4; sets with these values: 2; 치수 - 길이: 5050 mm
기본 벽:WA211-시멘트벽돌(일반) 벽 (0.5B) 90mm:5344631 | 지하1층 | 394.8 | 2596.09 | 2600 | 새 구성 | 벽 | CW112-스테인리스 스틸 커튼월 | 7675291 | 커튼월 | 커튼월: CW112-스테인리스 스틸 커튼월 | 6.74983 | CW112-스테인리스 스틸 커튼월 | 2 | ID 데이터 - 마크: 1; 해설: SSD; 구속조건 - 매스와 관련됨: no; 룸 경계: yes; 벽 베이스가 부착됩니다.: no; 상단이 부착됩니다.: no; 베이스 구속조건: 지하1층; 상단 구속조건: 상위 레벨: GL; 미연결 높이: 2600 mm; 베이스 간격띄우기: 200 mm; 상단 간격띄우기: -3150 mm; 구조 - 구조: no; 구조적 용도: 비교좌장치; 단면형상 정의 - 단면형상: 수직; 수직 그리드 - 각도: 0 deg; 간격띄우기: 0 mm; 맞춤: 시작; 번호: 4; sets with these values: 2; 치수 - 길이: 2596.09 mm
기본 벽:WA211-시멘트벽돌(일반) 벽 (0.5B) 90mm:5347520 | 지상 2층 | 394.8 | 6600 | 3020 | 새 구성 | 벽 | CW112-스테인리스 스틸 커튼월 | 7675291 | 커튼월 | 커튼월: CW112-스테인리스 스틸 커튼월 | 19.932 | CW112-스테인리스 스틸 커튼월 | 2 | ID 데이터 - 마크: 26; 해설: SSD; 구속조건 - 매스와 관련됨: no; 룸 경계: yes; 벽 베이스가 부착됩니다.: no; 상단이 부착됩니다.: no; 베이스 구속조건: 지상 2층; 상단 구속조건: 상위 레벨: 지상 3층; 미연결 높이: 3020 mm; 베이스 간격띄우기: 80 mm; 상단 간격띄우기: -1400 mm; 구조 - 구조: no; 구조적 용도: 비교좌장치; 단면형상 정의 - 단면형상: 수직; 수직 그리드 - 각도: 0 deg; 간격띄우기: 0 mm; 맞춤: 시작; 번호: 4; sets with these values: 2; 치수 - 길이: 6600 mm
기본 벽:WA211-시멘트벽돌(일반) 벽 (0.5B) 90mm:5347520 | 지상 2층 | 394.8 | 6500 | 3020 | 새 구성 | 벽 | CW112-스테인리스 스틸 커튼월 | 7675291 | 커튼월 | 커튼월: CW112-스테인리스 스틸 커튼월 | 19.63 | CW112-스테인리스 스틸 커튼월 | 2 | ID 데이터 - 마크: 27; 해설: SSD; 구속조건 - 매스와 관련됨: no; 룸 경계: yes; 벽 베이스가 부착됩니다.: no; 상단이 부착됩니다.: no; 베이스 구속조건: 지상 2층; 상단 구속조건: 상위 레벨: 지상 3층; 미연결 높이: 3020 mm; 베이스 간격띄우기: 80 mm; 상단 간격띄우기: -1400 mm; 구조 - 구조: no; 구조적 용도: 비교좌장치; 단면형상 정의 - 단면형상: 수직; 수직 그리드 - 각도: 0 deg; 간격띄우기: 0 mm; 맞춤: 시작; 번호: 4; sets with these values: 2; 치수 - 길이: 6500 mm
기본 벽:WA211-시멘트벽돌(일반) 벽 (0.5B) 90mm:5347520 | 지상 2층 | 394.8 | 2750 | 3020 | 새 구성 | 벽 | CW112-스테인리스 스틸 커튼월 | 7675291 | 커튼월 | 커튼월: CW112-스테인리스 스틸 커튼월 | 8.305 | CW112-스테인리스 스틸 커튼월 | 2 | ID 데이터 - 마크: 26; 해설: SSD; 구속조건 - 매스와 관련됨: no; 룸 경계: yes; 벽 베이스가 부착됩니다.: no; 상단이 부착됩니다.: no; 베이스 구속조건: 지상 2층; 상단 구속조건: 상위 레벨: 지상 3층; 미연결 높이: 3020 mm; 베이스 간격띄우기: 80 mm; 상단 간격띄우기: -1400 mm; 구조 - 구조: no; 구조적 용도: 비교좌장치; 단면형상 정의 - 단면형상: 수직; 수직 그리드 - 각도: 0 deg; 간격띄우기: 0 mm; 맞춤: 시작; 번호: 4; sets with these values: 2; 치수 - 길이: 2850 mm
기본 벽:WA211-시멘트벽돌(일반) 벽 (0.5B) 90mm:5351826 | 지상 2층 | 394.8 | 9900 | 3020 | 새 구성 | 벽 | CW112-스테인리스 스틸 커튼월 | 7675291 | 커튼월 | 커튼월: CW112-스테인리스 스틸 커튼월 | 29.898 | CW112-스테인리스 스틸 커튼월 | 2 | ID 데이터 - 마크: 28; 해설: SSD; 구속조건 - 매스와 관련됨: no; 룸 경계: yes; 벽 베이스가 부착됩니다.: no; 상단이 부착됩니다.: no; 베이스 구속조건: 지상 2층; 상단 구속조건: 상위 레벨: 지상 3층; 미연결 높이: 3020 mm; 베이스 간격띄우기: 80 mm; 상단 간격띄우기: -1400 mm; 구조 - 구조: no; 구조적 용도: 비교좌장치; 단면형상 정의 - 단면형상: 수직; 수직 그리드 - 각도: 0 deg; 간격띄우기: 0 mm; 맞춤: 시작; 번호: 4; sets with these values: 2; 치수 - 길이: 9900 mm
기본 벽:WA211-시멘트벽돌(일반) 벽 (0.5B) 90mm:5351826 | 지상 2층 | 394.8 | 3020 | 2499.97 | 새 구성 | 벽 | CW112-스테인리스 스틸 커튼월 | 7675291 | 커튼월 | 커튼월: CW112-스테인리스 스틸 커튼월 | 7.54992 | CW112-스테인리스 스틸 커튼월 | 2 | ID 데이터 - 마크: 25; 해설: SSD; 구속조건 - 매스와 관련됨: no; 룸 경계: yes; 벽 베이스가 부착됩니다.: no; 상단이 부착됩니다.: no; 베이스 구속조건: 지상 2층; 상단 구속조건: 상위 레벨: 지상 3층; 미연결 높이: 3020 mm; 베이스 간격띄우기: 80 mm; 상단 간격띄우기: -1400 mm; 구조 - 구조: no; 구조적 용도: 비교좌장치; 단면형상 정의 - 단면형상: 수직; 수직 그리드 - 각도: 0 deg; 간격띄우기: 0 mm; 맞춤: 시작; 번호: 4; sets with these values: 2; 치수 - 길이: 2499.97 mm
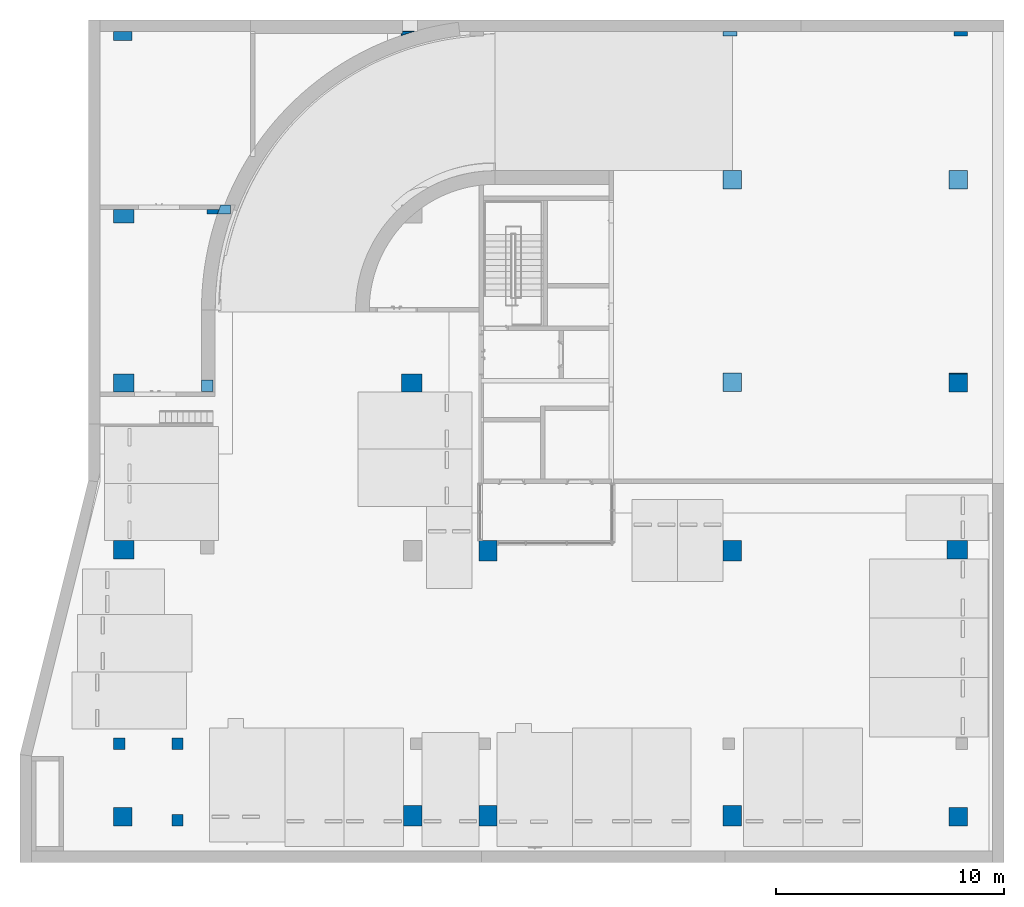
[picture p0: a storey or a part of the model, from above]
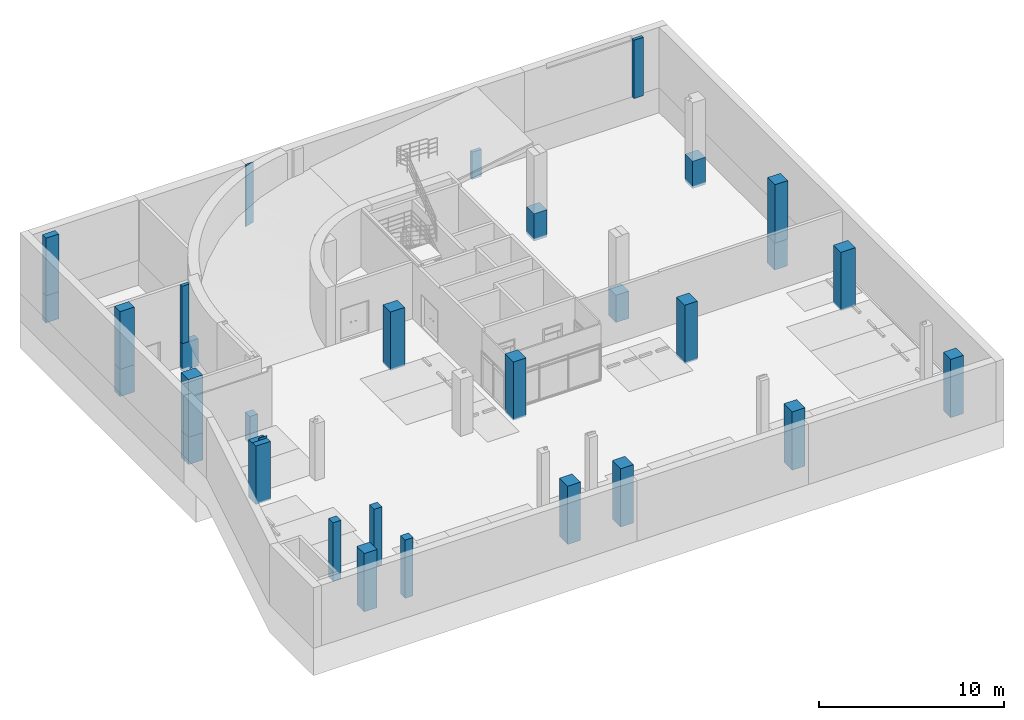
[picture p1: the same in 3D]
Properties of the parts of a building model (IFC2X3), part 25 of 39

# IfcOpeningElement: Opening (863)
Name | In | Depth (mm) | Height (mm) | Width (mm) | 생성 공정 | 카테고리 | 유형 | 유형 ID | 패밀리 | 패밀리 및 유형 | 면적 (m2) | Reference | Pset_OpeningElementCommon, sets with these values
기본 벽:WA211-시멘트벽돌(일반) 벽 (0.5B) 90mm:5351826 | 지상 2층 | 394.8 | 2218 | 3020 | 새 구성 | 벽 | CW112-스테인리스 스틸 커튼월 | 7675291 | 커튼월 | 커튼월: CW112-스테인리스 스틸 커튼월 | 6.69836 | CW112-스테인리스 스틸 커튼월 | 2 | ID 데이터 - 마크: 29; 해설: SSD; 구속조건 - 매스와 관련됨: no; 룸 경계: yes; 벽 베이스가 부착됩니다.: no; 상단이 부착됩니다.: no; 베이스 구속조건: 지상 2층; 상단 구속조건: 상위 레벨: 지상 3층; 미연결 높이: 3020 mm; 베이스 간격띄우기: 80 mm; 상단 간격띄우기: -1400 mm; 구조 - 구조: no; 구조적 용도: 비교좌장치; 단면형상 정의 - 단면형상: 수직; 수직 그리드 - 각도: 0 deg; 간격띄우기: 0 mm; 맞춤: 시작; 번호: 4; sets with these values: 2; 치수 - 길이: 2218 mm
기본 벽:WA211-시멘트벽돌(일반) 벽 (0.5B) 90mm:5352045 | 지상 2층 | 394.8 | 2499.97 | 3020 | 새 구성 | 벽 | CW112-스테인리스 스틸 커튼월 | 7675291 | 커튼월 | 커튼월: CW112-스테인리스 스틸 커튼월 | 7.54992 | CW112-스테인리스 스틸 커튼월 | 2 | ID 데이터 - 마크: 25; 해설: SSD; 구속조건 - 매스와 관련됨: no; 룸 경계: yes; 벽 베이스가 부착됩니다.: no; 상단이 부착됩니다.: no; 베이스 구속조건: 지상 2층; 상단 구속조건: 상위 레벨: 지상 3층; 미연결 높이: 3020 mm; 베이스 간격띄우기: 80 mm; 상단 간격띄우기: -1400 mm; 구조 - 구조: no; 구조적 용도: 비교좌장치; 단면형상 정의 - 단면형상: 수직; 수직 그리드 - 각도: 0 deg; 간격띄우기: 0 mm; 맞춤: 시작; 번호: 4; sets with these values: 2; 치수 - 길이: 2499.97 mm
기본 벽:WA211-시멘트벽돌(일반) 벽 (0.5B) 90mm:5352045 | 지상 2층 | 394.8 | 3020 | 9900 | 새 구성 | 벽 | CW112-스테인리스 스틸 커튼월 | 7675291 | 커튼월 | 커튼월: CW112-스테인리스 스틸 커튼월 | 29.898 | CW112-스테인리스 스틸 커튼월 | 2 | ID 데이터 - 마크: 28; 해설: SSD; 구속조건 - 매스와 관련됨: no; 룸 경계: yes; 벽 베이스가 부착됩니다.: no; 상단이 부착됩니다.: no; 베이스 구속조건: 지상 2층; 상단 구속조건: 상위 레벨: 지상 3층; 미연결 높이: 3020 mm; 베이스 간격띄우기: 80 mm; 상단 간격띄우기: -1400 mm; 구조 - 구조: no; 구조적 용도: 비교좌장치; 단면형상 정의 - 단면형상: 수직; 수직 그리드 - 각도: 0 deg; 간격띄우기: 0 mm; 맞춤: 시작; 번호: 4; sets with these values: 2; 치수 - 길이: 9900 mm
기본 벽:WA211-시멘트벽돌(일반) 벽 (0.5B) 90mm:5352045 | 지상 2층 | 394.8 | 3020 | 2218 | 새 구성 | 벽 | CW112-스테인리스 스틸 커튼월 | 7675291 | 커튼월 | 커튼월: CW112-스테인리스 스틸 커튼월 | 6.69836 | CW112-스테인리스 스틸 커튼월 | 2 | ID 데이터 - 마크: 29; 해설: SSD; 구속조건 - 매스와 관련됨: no; 룸 경계: yes; 벽 베이스가 부착됩니다.: no; 상단이 부착됩니다.: no; 베이스 구속조건: 지상 2층; 상단 구속조건: 상위 레벨: 지상 3층; 미연결 높이: 3020 mm; 베이스 간격띄우기: 80 mm; 상단 간격띄우기: -1400 mm; 구조 - 구조: no; 구조적 용도: 비교좌장치; 단면형상 정의 - 단면형상: 수직; 수직 그리드 - 각도: 0 deg; 간격띄우기: 0 mm; 맞춤: 시작; 번호: 4; sets with these values: 2; 치수 - 길이: 2218 mm
기본 벽:WA211-시멘트벽돌(일반) 벽 (0.5B) 90mm:5353459 | 지상 2층 | 394.8 | 2218 | 3020 | 새 구성 | 벽 | CW112-스테인리스 스틸 커튼월 | 7675291 | 커튼월 | 커튼월: CW112-스테인리스 스틸 커튼월 | 6.69836 | CW112-스테인리스 스틸 커튼월 | 2 | ID 데이터 - 마크: 29; 해설: SSD; 구속조건 - 매스와 관련됨: no; 룸 경계: yes; 벽 베이스가 부착됩니다.: no; 상단이 부착됩니다.: no; 베이스 구속조건: 지상 2층; 상단 구속조건: 상위 레벨: 지상 3층; 미연결 높이: 3020 mm; 베이스 간격띄우기: 80 mm; 상단 간격띄우기: -1400 mm; 구조 - 구조: no; 구조적 용도: 비교좌장치; 단면형상 정의 - 단면형상: 수직; 수직 그리드 - 각도: 0 deg; 간격띄우기: 0 mm; 맞춤: 시작; 번호: 4; sets with these values: 2; 치수 - 길이: 2218 mm
기본 벽:WA211-시멘트벽돌(일반) 벽 (0.5B) 90mm:5353459 | 지상 2층 | 394.8 | 3020 | 2499.97 | 새 구성 | 벽 | CW112-스테인리스 스틸 커튼월 | 7675291 | 커튼월 | 커튼월: CW112-스테인리스 스틸 커튼월 | 7.54992 | CW112-스테인리스 스틸 커튼월 | 2 | ID 데이터 - 마크: 25; 해설: SSD; 구속조건 - 매스와 관련됨: no; 룸 경계: yes; 벽 베이스가 부착됩니다.: no; 상단이 부착됩니다.: no; 베이스 구속조건: 지상 2층; 상단 구속조건: 상위 레벨: 지상 3층; 미연결 높이: 3020 mm; 베이스 간격띄우기: 80 mm; 상단 간격띄우기: -1400 mm; 구조 - 구조: no; 구조적 용도: 비교좌장치; 단면형상 정의 - 단면형상: 수직; 수직 그리드 - 각도: 0 deg; 간격띄우기: 0 mm; 맞춤: 시작; 번호: 4; sets with these values: 2; 치수 - 길이: 2499.97 mm
기본 벽:WA211-시멘트벽돌(일반) 벽 (0.5B) 90mm:5353459 | 지상 2층 | 394.8 | 9900 | 3020 | 새 구성 | 벽 | CW112-스테인리스 스틸 커튼월 | 7675291 | 커튼월 | 커튼월: CW112-스테인리스 스틸 커튼월 | 29.898 | CW112-스테인리스 스틸 커튼월 | 2 | ID 데이터 - 마크: 28; 해설: SSD; 구속조건 - 매스와 관련됨: no; 룸 경계: yes; 벽 베이스가 부착됩니다.: no; 상단이 부착됩니다.: no; 베이스 구속조건: 지상 2층; 상단 구속조건: 상위 레벨: 지상 3층; 미연결 높이: 3020 mm; 베이스 간격띄우기: 80 mm; 상단 간격띄우기: -1400 mm; 구조 - 구조: no; 구조적 용도: 비교좌장치; 단면형상 정의 - 단면형상: 수직; 수직 그리드 - 각도: 0 deg; 간격띄우기: 0 mm; 맞춤: 시작; 번호: 4; sets with these values: 2; 치수 - 길이: 9900 mm
기본 벽:WA211-시멘트벽돌(일반) 벽 (0.5B) 90mm:5353516 | 지상 3층 | 394.8 | 2750 | 2620 | 새 구성 | 벽 | CW112-스테인리스 스틸 커튼월 | 7675291 | 커튼월 | 커튼월: CW112-스테인리스 스틸 커튼월 | 7.205 | CW112-스테인리스 스틸 커튼월 | 2 | ID 데이터 - 마크: 26; 해설: SSD; 구속조건 - 매스와 관련됨: no; 룸 경계: yes; 벽 베이스가 부착됩니다.: no; 상단이 부착됩니다.: no; 베이스 구속조건: 지상 3층; 상단 구속조건: 상위 레벨: 지상 4층; 미연결 높이: 2620 mm; 베이스 간격띄우기: 80 mm; 상단 간격띄우기: -1400 mm; 구조 - 구조: no; 구조적 용도: 비교좌장치; 단면형상 정의 - 단면형상: 수직; 수직 그리드 - 각도: 0 deg; 간격띄우기: 0 mm; 맞춤: 시작; 번호: 4; sets with these values: 2; 치수 - 길이: 2850 mm
기본 벽:WA211-시멘트벽돌(일반) 벽 (0.5B) 90mm:5353516 | 지상 3층 | 394.8 | 6500.03 | 2620 | 새 구성 | 벽 | CW112-스테인리스 스틸 커튼월 | 7675291 | 커튼월 | 커튼월: CW112-스테인리스 스틸 커튼월 | 17.0301 | CW112-스테인리스 스틸 커튼월 | 2 | ID 데이터 - 마크: 27; 해설: SSD; 구속조건 - 매스와 관련됨: no; 룸 경계: yes; 벽 베이스가 부착됩니다.: no; 상단이 부착됩니다.: no; 베이스 구속조건: 지상 3층; 상단 구속조건: 상위 레벨: 지상 4층; 미연결 높이: 2620 mm; 베이스 간격띄우기: 80 mm; 상단 간격띄우기: -1400 mm; 구조 - 구조: no; 구조적 용도: 비교좌장치; 단면형상 정의 - 단면형상: 수직; 수직 그리드 - 각도: 0 deg; 간격띄우기: 0 mm; 맞춤: 시작; 번호: 4; sets with these values: 2; 치수 - 길이: 6500.03 mm
기본 벽:WA211-시멘트벽돌(일반) 벽 (0.5B) 90mm:5353516 | 지상 3층 | 394.8 | 6600 | 2620 | 새 구성 | 벽 | CW112-스테인리스 스틸 커튼월 | 7675291 | 커튼월 | 커튼월: CW112-스테인리스 스틸 커튼월 | 17.292 | CW112-스테인리스 스틸 커튼월 | 2 | ID 데이터 - 마크: 26; 해설: SSD; 구속조건 - 매스와 관련됨: no; 룸 경계: yes; 벽 베이스가 부착됩니다.: no; 상단이 부착됩니다.: no; 베이스 구속조건: 지상 3층; 상단 구속조건: 상위 레벨: 지상 4층; 미연결 높이: 2620 mm; 베이스 간격띄우기: 80 mm; 상단 간격띄우기: -1400 mm; 구조 - 구조: no; 구조적 용도: 비교좌장치; 단면형상 정의 - 단면형상: 수직; 수직 그리드 - 각도: 0 deg; 간격띄우기: 0 mm; 맞춤: 시작; 번호: 4; sets with these values: 2; 치수 - 길이: 6600 mm
기본 벽:WA211-시멘트벽돌(일반) 벽 (0.5B) 90mm:5353543 | 지상 3층 | 394.8 | 6600 | 2620 | 새 구성 | 벽 | CW112-스테인리스 스틸 커튼월 | 7675291 | 커튼월 | 커튼월: CW112-스테인리스 스틸 커튼월 | 17.292 | CW112-스테인리스 스틸 커튼월 | 2 | ID 데이터 - 마크: 26; 해설: SSD; 구속조건 - 매스와 관련됨: no; 룸 경계: yes; 벽 베이스가 부착됩니다.: no; 상단이 부착됩니다.: no; 베이스 구속조건: 지상 3층; 상단 구속조건: 상위 레벨: 지상 4층; 미연결 높이: 2620 mm; 베이스 간격띄우기: 80 mm; 상단 간격띄우기: -1400 mm; 구조 - 구조: no; 구조적 용도: 비교좌장치; 단면형상 정의 - 단면형상: 수직; 수직 그리드 - 각도: 0 deg; 간격띄우기: 0 mm; 맞춤: 시작; 번호: 4; sets with these values: 2; 치수 - 길이: 6600 mm
기본 벽:WA211-시멘트벽돌(일반) 벽 (0.5B) 90mm:5353543 | 지상 3층 | 394.8 | 2750 | 2620 | 새 구성 | 벽 | CW112-스테인리스 스틸 커튼월 | 7675291 | 커튼월 | 커튼월: CW112-스테인리스 스틸 커튼월 | 7.205 | CW112-스테인리스 스틸 커튼월 | 2 | ID 데이터 - 마크: 26; 해설: SSD; 구속조건 - 매스와 관련됨: no; 룸 경계: yes; 벽 베이스가 부착됩니다.: no; 상단이 부착됩니다.: no; 베이스 구속조건: 지상 3층; 상단 구속조건: 상위 레벨: 지상 4층; 미연결 높이: 2620 mm; 베이스 간격띄우기: 80 mm; 상단 간격띄우기: -1400 mm; 구조 - 구조: no; 구조적 용도: 비교좌장치; 단면형상 정의 - 단면형상: 수직; 수직 그리드 - 각도: 0 deg; 간격띄우기: 0 mm; 맞춤: 시작; 번호: 4; sets with these values: 2; 치수 - 길이: 2850 mm
기본 벽:WA211-시멘트벽돌(일반) 벽 (0.5B) 90mm:5353543 | 지상 3층 | 394.8 | 6500.03 | 2620 | 새 구성 | 벽 | CW112-스테인리스 스틸 커튼월 | 7675291 | 커튼월 | 커튼월: CW112-스테인리스 스틸 커튼월 | 17.0301 | CW112-스테인리스 스틸 커튼월 | 2 | ID 데이터 - 마크: 27; 해설: SSD; 구속조건 - 매스와 관련됨: no; 룸 경계: yes; 벽 베이스가 부착됩니다.: no; 상단이 부착됩니다.: no; 베이스 구속조건: 지상 3층; 상단 구속조건: 상위 레벨: 지상 4층; 미연결 높이: 2620 mm; 베이스 간격띄우기: 80 mm; 상단 간격띄우기: -1400 mm; 구조 - 구조: no; 구조적 용도: 비교좌장치; 단면형상 정의 - 단면형상: 수직; 수직 그리드 - 각도: 0 deg; 간격띄우기: 0 mm; 맞춤: 시작; 번호: 4; sets with these values: 2; 치수 - 길이: 6500.03 mm
기본 벽:WA211-시멘트벽돌(일반) 벽 (0.5B) 90mm:5354023 | 지상 3층 | 394.8 |  |  | 새 구성 | 벽 | CW112-스테인리스 스틸 커튼월 | 7675291 | 커튼월 | 커튼월: CW112-스테인리스 스틸 커튼월 | 3.43748 | CW112-스테인리스 스틸 커튼월 | 2 | ID 데이터 - 마크: 25; 해설: SSD; 구속조건 - 매스와 관련됨: no; 룸 경계: yes; 벽 베이스가 부착됩니다.: no; 상단이 부착됩니다.: no; 베이스 구속조건: 지상 3층; 상단 구속조건: 상위 레벨: 지상 4층; 미연결 높이: 2620 mm; 베이스 간격띄우기: 80 mm; 상단 간격띄우기: -1400 mm; 구조 - 구조: no; 구조적 용도: 비교좌장치; 단면형상 정의 - 단면형상: 수직; 수직 그리드 - 각도: 0 deg; 간격띄우기: 0 mm; 맞춤: 시작; 번호: 4; sets with these values: 2; 치수 - 길이: 2499.99 mm; BaseQuantities - Area: 3.43748 m2
기본 벽:WA211-시멘트벽돌(일반) 벽 (0.5B) 90mm:5354023 | 지상 3층 | 394.8 |  |  | 새 구성 | 벽 | CW112-스테인리스 스틸 커튼월 | 7675291 | 커튼월 | 커튼월: CW112-스테인리스 스틸 커튼월 | 22.8255 | CW112-스테인리스 스틸 커튼월 | 2 | ID 데이터 - 마크: 28; 해설: SSD; 구속조건 - 매스와 관련됨: no; 룸 경계: yes; 벽 베이스가 부착됩니다.: no; 상단이 부착됩니다.: no; 베이스 구속조건: 지상 3층; 상단 구속조건: 상위 레벨: 지상 4층; 미연결 높이: 2620 mm; 베이스 간격띄우기: 80 mm; 상단 간격띄우기: -1400 mm; 구조 - 구조: no; 구조적 용도: 비교좌장치; 단면형상 정의 - 단면형상: 수직; 수직 그리드 - 각도: 0 deg; 간격띄우기: 0 mm; 맞춤: 시작; 번호: 4; sets with these values: 2; 치수 - 길이: 9900.02 mm; BaseQuantities - Area: 22.8255 m2
기본 벽:WA211-시멘트벽돌(일반) 벽 (0.5B) 90mm:5354023 | 지상 3층 | 394.8 | 2620 | 2250 | 새 구성 | 벽 | CW112-스테인리스 스틸 커튼월 | 7675291 | 커튼월 | 커튼월: CW112-스테인리스 스틸 커튼월 | 5.895 | CW112-스테인리스 스틸 커튼월 | 2 | ID 데이터 - 마크: 29; 해설: SSD; 구속조건 - 매스와 관련됨: no; 룸 경계: yes; 벽 베이스가 부착됩니다.: no; 상단이 부착됩니다.: no; 베이스 구속조건: 지상 3층; 상단 구속조건: 상위 레벨: 지상 4층; 미연결 높이: 2620 mm; 베이스 간격띄우기: 80 mm; 상단 간격띄우기: -1400 mm; 구조 - 구조: no; 구조적 용도: 비교좌장치; 단면형상 정의 - 단면형상: 수직; 수직 그리드 - 각도: 0 deg; 간격띄우기: 0 mm; 맞춤: 시작; 번호: 4; sets with these values: 2; 치수 - 길이: 2250 mm
기본 벽:WA211-시멘트벽돌(일반) 벽 (0.5B) 90mm:5354023 | 지상 3층 | 3048 | 1500 | 2100 | 새 구성 | 문 | DR121-쌍여닫이문(유리, 일반, 양개) 1500x2100mm | 7693130 | DR121-쌍여닫이문(철재, 일반, 양개) | DR121-쌍여닫이문(철재, 일반, 양개): DR121-쌍여닫이문(유리, 일반, 양개) 1500x2100mm | 3.7857 | DR121-쌍여닫이문(유리, 일반, 양개) 1500x2100mm | 2 | ID 데이터 - 마크: 25WWWWW; 구속조건 - 레벨: 지상 3층; 씰 높이: 55 mm; 기타 - 헤드 높이: 2155 mm; 호스트 ID: 5354050; 치수 - 체적: 0.0603055 m3; 데이터 - 벽체 opening 면적: 3.15 m2
기본 벽:WA211-시멘트벽돌(일반) 벽 (0.5B) 90mm:5354050 | 지상 3층 | 394.8 |  |  | 새 구성 | 벽 | CW112-스테인리스 스틸 커튼월 | 7675291 | 커튼월 | 커튼월: CW112-스테인리스 스틸 커튼월 | 22.8255 | CW112-스테인리스 스틸 커튼월 | 2 | ID 데이터 - 마크: 28; 해설: SSD; 구속조건 - 매스와 관련됨: no; 룸 경계: yes; 벽 베이스가 부착됩니다.: no; 상단이 부착됩니다.: no; 베이스 구속조건: 지상 3층; 상단 구속조건: 상위 레벨: 지상 4층; 미연결 높이: 2620 mm; 베이스 간격띄우기: 80 mm; 상단 간격띄우기: -1400 mm; 구조 - 구조: no; 구조적 용도: 비교좌장치; 단면형상 정의 - 단면형상: 수직; 수직 그리드 - 각도: 0 deg; 간격띄우기: 0 mm; 맞춤: 시작; 번호: 4; sets with these values: 2; 치수 - 길이: 9900.02 mm; BaseQuantities - Area: 22.8255 m2
기본 벽:WA211-시멘트벽돌(일반) 벽 (0.5B) 90mm:5354231 | 지상 3층 | 394.8 | 2250 | 2620 | 새 구성 | 벽 | CW112-스테인리스 스틸 커튼월 | 7675291 | 커튼월 | 커튼월: CW112-스테인리스 스틸 커튼월 | 5.895 | CW112-스테인리스 스틸 커튼월 | 2 | ID 데이터 - 마크: 29; 해설: SSD; 구속조건 - 매스와 관련됨: no; 룸 경계: yes; 벽 베이스가 부착됩니다.: no; 상단이 부착됩니다.: no; 베이스 구속조건: 지상 3층; 상단 구속조건: 상위 레벨: 지상 4층; 미연결 높이: 2620 mm; 베이스 간격띄우기: 80 mm; 상단 간격띄우기: -1400 mm; 구조 - 구조: no; 구조적 용도: 비교좌장치; 단면형상 정의 - 단면형상: 수직; 수직 그리드 - 각도: 0 deg; 간격띄우기: 0 mm; 맞춤: 시작; 번호: 4; sets with these values: 2; 치수 - 길이: 2250 mm
기본 벽:WA211-시멘트벽돌(일반) 벽 (0.5B) 90mm:5354243 | 지상 3층 | 3048 | 1800 | 2100 | 새 구성 | 문 | DR121-쌍여닫이문(철재, 방화문) 1800x2100mm | 7435628 | DR121-쌍여닫이문(철재, 방화문) | DR121-쌍여닫이문(철재, 방화문): DR121-쌍여닫이문(철재, 방화문) 1800x2100mm | 5.32025 | DR121-쌍여닫이문(철재, 방화문) 1800x2100mm | 2 | 구속조건 - 레벨: 지상 3층; 씰 높이: 80 mm; 기타 - 헤드 높이: 2180 mm; 호스트 ID: 2820467; 치수 - 체적: 0.146498 m3; 데이터 - 벽체 opening 면적: 3.78 m2
기본 벽:WA211-시멘트벽돌(일반) 벽 (0.5B) 90mm:5354243 | 지상 3층 | 394.8 | 2850 | 2620 | 새 구성 | 벽 | CW112-스테인리스 스틸 커튼월 | 7675291 | 커튼월 | 커튼월: CW112-스테인리스 스틸 커튼월 | 7.467 | CW112-스테인리스 스틸 커튼월 | 2 | ID 데이터 - 해설: SSD; 구속조건 - 매스와 관련됨: no; 룸 경계: yes; 벽 베이스가 부착됩니다.: no; 상단이 부착됩니다.: no; 베이스 구속조건: 지상 3층; 상단 구속조건: 상위 레벨: 지상 4층; 미연결 높이: 2620 mm; 베이스 간격띄우기: 80 mm; 상단 간격띄우기: -1400 mm; 구조 - 구조: no; 구조적 용도: 비교좌장치; 단면형상 정의 - 단면형상: 수직; 수직 그리드 - 각도: 0 deg; 간격띄우기: 0 mm; 맞춤: 시작; 번호: 4; sets with these values: 2; 치수 - 길이: 2850 mm
기본 벽:WA211-시멘트벽돌(일반) 벽 (0.5B) 90mm:5355598 | 지상 4층 | 394.8 | 2500 | 2620 | 새 구성 | 벽 | CW112-스테인리스 스틸 커튼월 | 7675291 | 커튼월 | 커튼월: CW112-스테인리스 스틸 커튼월 | 6.55 | CW112-스테인리스 스틸 커튼월 | 2 | ID 데이터 - 마크: 25; 해설: SSD; 구속조건 - 매스와 관련됨: no; 룸 경계: yes; 벽 베이스가 부착됩니다.: no; 상단이 부착됩니다.: no; 베이스 구속조건: 지상 4층; 상단 구속조건: 상위 레벨: 지상 5층; 미연결 높이: 2620 mm; 베이스 간격띄우기: 80 mm; 상단 간격띄우기: -1400 mm; 구조 - 구조: no; 구조적 용도: 비교좌장치; 단면형상 정의 - 단면형상: 수직; 수직 그리드 - 각도: 0 deg; 간격띄우기: 0 mm; 맞춤: 시작; 번호: 4; sets with these values: 2; 치수 - 길이: 2600 mm
기본 벽:WA211-시멘트벽돌(일반) 벽 (0.5B) 90mm:5355599 | 지상 4층 | 394.8 |  |  | 새 구성 | 벽 | CW112-스테인리스 스틸 커튼월 | 7675291 | 커튼월 | 커튼월: CW112-스테인리스 스틸 커튼월 | 14.1795 | CW112-스테인리스 스틸 커튼월 | 2 | ID 데이터 - 마크: 26; 해설: SSD; 구속조건 - 매스와 관련됨: no; 룸 경계: yes; 벽 베이스가 부착됩니다.: no; 상단이 부착됩니다.: no; 베이스 구속조건: 지상 4층; 상단 구속조건: 상위 레벨: 지상 5층; 미연결 높이: 2620 mm; 베이스 간격띄우기: 80 mm; 상단 간격띄우기: -1400 mm; 구조 - 구조: no; 구조적 용도: 비교좌장치; 단면형상 정의 - 단면형상: 수직; 수직 그리드 - 각도: 0 deg; 간격띄우기: 0 mm; 맞춤: 시작; 번호: 4; sets with these values: 2; 치수 - 길이: 6600 mm; BaseQuantities - Area: 14.1795 m2
기본 벽:WA211-시멘트벽돌(일반) 벽 (0.5B) 90mm:5355601 | 지상 4층 | 394.8 | 2500.03 | 2620 | 새 구성 | 벽 | CW112-스테인리스 스틸 커튼월 | 7675291 | 커튼월 | 커튼월: CW112-스테인리스 스틸 커튼월 | 6.55009 | CW112-스테인리스 스틸 커튼월 | 2 | ID 데이터 - 마크: 25; 해설: SSD; 구속조건 - 매스와 관련됨: no; 룸 경계: yes; 벽 베이스가 부착됩니다.: no; 상단이 부착됩니다.: no; 베이스 구속조건: 지상 4층; 상단 구속조건: 상위 레벨: 지상 5층; 미연결 높이: 2620 mm; 베이스 간격띄우기: 80 mm; 상단 간격띄우기: -1400 mm; 구조 - 구조: no; 구조적 용도: 비교좌장치; 단면형상 정의 - 단면형상: 수직; 수직 그리드 - 각도: 0 deg; 간격띄우기: 0 mm; 맞춤: 시작; 번호: 4; sets with these values: 2; 치수 - 길이: 2500.03 mm
기본 벽:WA211-시멘트벽돌(일반) 벽 (0.5B) 90mm:5355602 | 지상 4층 | 394.8 | 9900 | 2620 | 새 구성 | 벽 | CW112-스테인리스 스틸 커튼월 | 7675291 | 커튼월 | 커튼월: CW112-스테인리스 스틸 커튼월 | 25.938 | CW112-스테인리스 스틸 커튼월 | 2 | ID 데이터 - 마크: 28; 해설: SSD; 구속조건 - 매스와 관련됨: no; 룸 경계: yes; 벽 베이스가 부착됩니다.: no; 상단이 부착됩니다.: no; 베이스 구속조건: 지상 4층; 상단 구속조건: 상위 레벨: 지상 5층; 미연결 높이: 2620 mm; 베이스 간격띄우기: 80 mm; 상단 간격띄우기: -1400 mm; 구조 - 구조: no; 구조적 용도: 비교좌장치; 단면형상 정의 - 단면형상: 수직; 수직 그리드 - 각도: 0 deg; 간격띄우기: 0 mm; 맞춤: 시작; 번호: 4; sets with these values: 2; 치수 - 길이: 9900 mm
기본 벽:WA211-시멘트벽돌(일반) 벽 (0.5B) 90mm:5355603 | 지상 4층 | 394.8 | 2235 | 2620 | 새 구성 | 벽 | CW112-스테인리스 스틸 커튼월 | 7675291 | 커튼월 | 커튼월: CW112-스테인리스 스틸 커튼월 | 5.8557 | CW112-스테인리스 스틸 커튼월 | 2 | ID 데이터 - 마크: 29; 해설: SSD; 구속조건 - 매스와 관련됨: no; 룸 경계: yes; 벽 베이스가 부착됩니다.: no; 상단이 부착됩니다.: no; 베이스 구속조건: 지상 4층; 상단 구속조건: 상위 레벨: 지상 5층; 미연결 높이: 2620 mm; 베이스 간격띄우기: 80 mm; 상단 간격띄우기: -1400 mm; 구조 - 구조: no; 구조적 용도: 비교좌장치; 단면형상 정의 - 단면형상: 수직; 수직 그리드 - 각도: 0 deg; 간격띄우기: 0 mm; 맞춤: 시작; 번호: 4; sets with these values: 2; 치수 - 길이: 2235 mm
기본 벽:WA211-시멘트벽돌(일반) 벽 (0.5B) 90mm:5355604 | 지상 4층 | 394.8 |  |  | 새 구성 | 벽 | CW112-스테인리스 스틸 커튼월 | 7675291 | 커튼월 | 커튼월: CW112-스테인리스 스틸 커튼월 | 3.93539 | CW112-스테인리스 스틸 커튼월 | 2 | ID 데이터 - 마크: 29; 해설: SSD; 구속조건 - 매스와 관련됨: no; 룸 경계: yes; 벽 베이스가 부착됩니다.: no; 상단이 부착됩니다.: no; 베이스 구속조건: 지상 4층; 상단 구속조건: 상위 레벨: 지상 5층; 미연결 높이: 2620 mm; 베이스 간격띄우기: 80 mm; 상단 간격띄우기: -1400 mm; 구조 - 구조: no; 구조적 용도: 비교좌장치; 단면형상 정의 - 단면형상: 수직; 수직 그리드 - 각도: 0 deg; 간격띄우기: 0 mm; 맞춤: 시작; 번호: 4; sets with these values: 2; 치수 - 길이: 2690.03 mm; BaseQuantities - Area: 3.93539 m2
기본 벽:WA211-시멘트벽돌(일반) 벽 (0.5B) 90mm:5355605 | 지상 4층 | 394.8 |  |  | 새 구성 | 벽 | CW112-스테인리스 스틸 커튼월 | 7675291 | 커튼월 | 커튼월: CW112-스테인리스 스틸 커튼월 | 4.09252 | CW112-스테인리스 스틸 커튼월 | 2 | ID 데이터 - 마크: 29; 해설: SSD; 구속조건 - 매스와 관련됨: no; 룸 경계: yes; 벽 베이스가 부착됩니다.: no; 상단이 부착됩니다.: no; 베이스 구속조건: 지상 4층; 상단 구속조건: 상위 레벨: 지상 5층; 미연결 높이: 2620 mm; 베이스 간격띄우기: 80 mm; 상단 간격띄우기: -1400 mm; 구조 - 구조: no; 구조적 용도: 비교좌장치; 단면형상 정의 - 단면형상: 수직; 수직 그리드 - 각도: 0 deg; 간격띄우기: 0 mm; 맞춤: 시작; 번호: 4; sets with these values: 2; 치수 - 길이: 2750.01 mm; BaseQuantities - Area: 4.09252 m2
기본 벽:WA211-시멘트벽돌(일반) 벽 (0.5B) 90mm:5355816 | 지상 5층 | 394.8 |  |  | 새 구성 | 벽 | CW112-스테인리스 스틸 커튼월 | 7675291 | 커튼월 | 커튼월: CW112-스테인리스 스틸 커튼월 | 3.54125 | CW112-스테인리스 스틸 커튼월 | 2 | ID 데이터 - 마크: 25; 해설: SSD; 구속조건 - 매스와 관련됨: no; 룸 경계: yes; 벽 베이스가 부착됩니다.: no; 상단이 부착됩니다.: no; 베이스 구속조건: 지상 5층; 상단 구속조건: 상위 레벨: 지상 6층; 미연결 높이: 2620 mm; 베이스 간격띄우기: 80 mm; 상단 간격띄우기: -1400 mm; 구조 - 구조: no; 구조적 용도: 비교좌장치; 단면형상 정의 - 단면형상: 수직; 수직 그리드 - 각도: 0 deg; 간격띄우기: 0 mm; 맞춤: 시작; 번호: 4; sets with these values: 2; 치수 - 길이: 2600 mm; BaseQuantities - Area: 3.54125 m2
기본 벽:WA211-시멘트벽돌(일반) 벽 (0.5B) 90mm:5355817 | 지상 5층 | 394.8 |  |  | 새 구성 | 벽 | CW112-스테인리스 스틸 커튼월 | 7675291 | 커튼월 | 커튼월: CW112-스테인리스 스틸 커튼월 | 14.1795 | CW112-스테인리스 스틸 커튼월 | 2 | ID 데이터 - 마크: 26; 해설: SSD; 구속조건 - 매스와 관련됨: no; 룸 경계: yes; 벽 베이스가 부착됩니다.: no; 상단이 부착됩니다.: no; 베이스 구속조건: 지상 5층; 상단 구속조건: 상위 레벨: 지상 6층; 미연결 높이: 2620 mm; 베이스 간격띄우기: 80 mm; 상단 간격띄우기: -1400 mm; 구조 - 구조: no; 구조적 용도: 비교좌장치; 단면형상 정의 - 단면형상: 수직; 수직 그리드 - 각도: 0 deg; 간격띄우기: 0 mm; 맞춤: 시작; 번호: 4; sets with these values: 2; 치수 - 길이: 6600 mm; BaseQuantities - Area: 14.1795 m2
기본 벽:WA211-시멘트벽돌(일반) 벽 (0.5B) 90mm:5355819 | 지상 5층 | 394.8 |  |  | 새 구성 | 벽 | CW112-스테인리스 스틸 커튼월 | 7675291 | 커튼월 | 커튼월: CW112-스테인리스 스틸 커튼월 | 3.43755 | CW112-스테인리스 스틸 커튼월 | 2 | ID 데이터 - 마크: 25; 해설: SSD; 구속조건 - 매스와 관련됨: no; 룸 경계: yes; 벽 베이스가 부착됩니다.: no; 상단이 부착됩니다.: no; 베이스 구속조건: 지상 5층; 상단 구속조건: 상위 레벨: 지상 6층; 미연결 높이: 2620 mm; 베이스 간격띄우기: 80 mm; 상단 간격띄우기: -1400 mm; 구조 - 구조: no; 구조적 용도: 비교좌장치; 단면형상 정의 - 단면형상: 수직; 수직 그리드 - 각도: 0 deg; 간격띄우기: 0 mm; 맞춤: 시작; 번호: 4; sets with these values: 2; 치수 - 길이: 2500.02 mm; BaseQuantities - Area: 3.43755 m2
기본 벽:WA211-시멘트벽돌(일반) 벽 (0.5B) 90mm:5355820 | 지상 5층 | 394.8 |  |  | 새 구성 | 벽 | CW112-스테인리스 스틸 커튼월 | 7675291 | 커튼월 | 커튼월: CW112-스테인리스 스틸 커튼월 | 22.8255 | CW112-스테인리스 스틸 커튼월 | 2 | ID 데이터 - 마크: 28; 해설: SSD; 구속조건 - 매스와 관련됨: no; 룸 경계: yes; 벽 베이스가 부착됩니다.: no; 상단이 부착됩니다.: no; 베이스 구속조건: 지상 5층; 상단 구속조건: 상위 레벨: 지상 6층; 미연결 높이: 2620 mm; 베이스 간격띄우기: 80 mm; 상단 간격띄우기: -1400 mm; 구조 - 구조: no; 구조적 용도: 비교좌장치; 단면형상 정의 - 단면형상: 수직; 수직 그리드 - 각도: 0 deg; 간격띄우기: 0 mm; 맞춤: 시작; 번호: 4; sets with these values: 2; 치수 - 길이: 9900.02 mm; BaseQuantities - Area: 22.8255 m2
기본 벽:WA211-시멘트벽돌(일반) 벽 (0.5B) 90mm:5355821 | 지상 5층 | 394.8 | 2195 | 2620 | 새 구성 | 벽 | CW112-스테인리스 스틸 커튼월 | 7675291 | 커튼월 | 커튼월: CW112-스테인리스 스틸 커튼월 | 5.7509 | CW112-스테인리스 스틸 커튼월 | 2 | ID 데이터 - 마크: 29; 해설: SSD; 구속조건 - 매스와 관련됨: no; 룸 경계: yes; 벽 베이스가 부착됩니다.: no; 상단이 부착됩니다.: no; 베이스 구속조건: 지상 5층; 상단 구속조건: 상위 레벨: 지상 6층; 미연결 높이: 2620 mm; 베이스 간격띄우기: 80 mm; 상단 간격띄우기: -1400 mm; 구조 - 구조: no; 구조적 용도: 비교좌장치; 단면형상 정의 - 단면형상: 수직; 수직 그리드 - 각도: 0 deg; 간격띄우기: 0 mm; 맞춤: 시작; 번호: 4; sets with these values: 2; 치수 - 길이: 2195 mm
기본 벽:WA211-시멘트벽돌(일반) 벽 (0.5B) 90mm:5355822 | 지상 5층 | 394.8 |  |  | 새 구성 | 벽 | CW112-스테인리스 스틸 커튼월 | 7675291 | 커튼월 | 커튼월: CW112-스테인리스 스틸 커튼월 | 3.93792 | CW112-스테인리스 스틸 커튼월 | 2 | ID 데이터 - 마크: 29; 해설: SSD; 구속조건 - 매스와 관련됨: no; 룸 경계: yes; 벽 베이스가 부착됩니다.: no; 상단이 부착됩니다.: no; 베이스 구속조건: 지상 5층; 상단 구속조건: 상위 레벨: 지상 6층; 미연결 높이: 2620 mm; 베이스 간격띄우기: 80 mm; 상단 간격띄우기: -1400 mm; 구조 - 구조: no; 구조적 용도: 비교좌장치; 단면형상 정의 - 단면형상: 수직; 수직 그리드 - 각도: 0 deg; 간격띄우기: 0 mm; 맞춤: 시작; 번호: 4; sets with these values: 2; 치수 - 길이: 2700 mm; BaseQuantities - Area: 3.93792 m2
기본 벽:WA211-시멘트벽돌(일반) 벽 (0.5B) 90mm:5355823 | 지상 5층 | 394.8 |  |  | 새 구성 | 벽 | CW112-스테인리스 스틸 커튼월 | 7675291 | 커튼월 | 커튼월: CW112-스테인리스 스틸 커튼월 | 4.2235 | CW112-스테인리스 스틸 커튼월 | 2 | ID 데이터 - 마크: 29; 해설: SSD; 구속조건 - 매스와 관련됨: no; 룸 경계: yes; 벽 베이스가 부착됩니다.: no; 상단이 부착됩니다.: no; 베이스 구속조건: 지상 5층; 상단 구속조건: 상위 레벨: 지상 6층; 미연결 높이: 2620 mm; 베이스 간격띄우기: 80 mm; 상단 간격띄우기: -1400 mm; 구조 - 구조: no; 구조적 용도: 비교좌장치; 단면형상 정의 - 단면형상: 수직; 수직 그리드 - 각도: 0 deg; 간격띄우기: 0 mm; 맞춤: 시작; 번호: 4; sets with these values: 2; 치수 - 길이: 2800 mm; BaseQuantities - Area: 4.2235 m2
기본 벽:WA211-시멘트벽돌(일반) 벽 (0.5B) 90mm:5356034 | 지상 6층 | 394.8 |  |  | 새 구성 | 벽 | CW112-스테인리스 스틸 커튼월 | 7675291 | 커튼월 | 커튼월: CW112-스테인리스 스틸 커튼월 | 3.54127 | CW112-스테인리스 스틸 커튼월 | 2 | ID 데이터 - 마크: 25; 해설: SSD; 구속조건 - 매스와 관련됨: no; 룸 경계: yes; 벽 베이스가 부착됩니다.: no; 상단이 부착됩니다.: no; 베이스 구속조건: 지상 6층; 상단 구속조건: 상위 레벨: 지상 7층; 미연결 높이: 2620 mm; 베이스 간격띄우기: 80 mm; 상단 간격띄우기: -1400 mm; 구조 - 구조: no; 구조적 용도: 비교좌장치; 단면형상 정의 - 단면형상: 수직; 수직 그리드 - 각도: 0 deg; 간격띄우기: 0 mm; 맞춤: 시작; 번호: 4; sets with these values: 2; 치수 - 길이: 2600.01 mm; BaseQuantities - Area: 3.54127 m2
기본 벽:WA211-시멘트벽돌(일반) 벽 (0.5B) 90mm:5356035 | 지상 6층 | 394.8 |  |  | 새 구성 | 벽 | CW112-스테인리스 스틸 커튼월 | 7675291 | 커튼월 | 커튼월: CW112-스테인리스 스틸 커튼월 | 14.1795 | CW112-스테인리스 스틸 커튼월 | 2 | ID 데이터 - 마크: 26; 해설: SSD; 구속조건 - 매스와 관련됨: no; 룸 경계: yes; 벽 베이스가 부착됩니다.: no; 상단이 부착됩니다.: no; 베이스 구속조건: 지상 6층; 상단 구속조건: 상위 레벨: 지상 7층; 미연결 높이: 2620 mm; 베이스 간격띄우기: 80 mm; 상단 간격띄우기: -1400 mm; 구조 - 구조: no; 구조적 용도: 비교좌장치; 단면형상 정의 - 단면형상: 수직; 수직 그리드 - 각도: 0 deg; 간격띄우기: 0 mm; 맞춤: 시작; 번호: 4; sets with these values: 2; 치수 - 길이: 6600 mm; BaseQuantities - Area: 14.1795 m2
기본 벽:WA211-시멘트벽돌(일반) 벽 (0.5B) 90mm:5356037 | 지상 6층 | 394.8 |  |  | 새 구성 | 벽 | CW112-스테인리스 스틸 커튼월 | 7675291 | 커튼월 | 커튼월: CW112-스테인리스 스틸 커튼월 | 3.4375 | CW112-스테인리스 스틸 커튼월 | 2 | ID 데이터 - 마크: 25; 해설: SSD; 구속조건 - 매스와 관련됨: no; 룸 경계: yes; 벽 베이스가 부착됩니다.: no; 상단이 부착됩니다.: no; 베이스 구속조건: 지상 6층; 상단 구속조건: 상위 레벨: 지상 7층; 미연결 높이: 2620 mm; 베이스 간격띄우기: 80 mm; 상단 간격띄우기: -1400 mm; 구조 - 구조: no; 구조적 용도: 비교좌장치; 단면형상 정의 - 단면형상: 수직; 수직 그리드 - 각도: 0 deg; 간격띄우기: 0 mm; 맞춤: 시작; 번호: 4; sets with these values: 2; 치수 - 길이: 2500 mm; BaseQuantities - Area: 3.4375 m2
기본 벽:WA211-시멘트벽돌(일반) 벽 (0.5B) 90mm:5356038 | 지상 6층 | 394.8 |  |  | 새 구성 | 벽 | CW112-스테인리스 스틸 커튼월 | 7675291 | 커튼월 | 커튼월: CW112-스테인리스 스틸 커튼월 | 22.8254 | CW112-스테인리스 스틸 커튼월 | 2 | ID 데이터 - 마크: 28; 해설: SSD; 구속조건 - 매스와 관련됨: no; 룸 경계: yes; 벽 베이스가 부착됩니다.: no; 상단이 부착됩니다.: no; 베이스 구속조건: 지상 6층; 상단 구속조건: 상위 레벨: 지상 7층; 미연결 높이: 2620 mm; 베이스 간격띄우기: 80 mm; 상단 간격띄우기: -1400 mm; 구조 - 구조: no; 구조적 용도: 비교좌장치; 단면형상 정의 - 단면형상: 수직; 수직 그리드 - 각도: 0 deg; 간격띄우기: 0 mm; 맞춤: 시작; 번호: 4; sets with these values: 2; 치수 - 길이: 9899.98 mm; BaseQuantities - Area: 22.8254 m2
기본 벽:WA211-시멘트벽돌(일반) 벽 (0.5B) 90mm:5356039 | 지상 6층 | 394.8 | 2195 | 2620 | 새 구성 | 벽 | CW112-스테인리스 스틸 커튼월 | 7675291 | 커튼월 | 커튼월: CW112-스테인리스 스틸 커튼월 | 5.7509 | CW112-스테인리스 스틸 커튼월 | 2 | ID 데이터 - 마크: 29; 해설: SSD; 구속조건 - 매스와 관련됨: no; 룸 경계: yes; 벽 베이스가 부착됩니다.: no; 상단이 부착됩니다.: no; 베이스 구속조건: 지상 6층; 상단 구속조건: 상위 레벨: 지상 7층; 미연결 높이: 2620 mm; 베이스 간격띄우기: 80 mm; 상단 간격띄우기: -1400 mm; 구조 - 구조: no; 구조적 용도: 비교좌장치; 단면형상 정의 - 단면형상: 수직; 수직 그리드 - 각도: 0 deg; 간격띄우기: 0 mm; 맞춤: 시작; 번호: 4; sets with these values: 2; 치수 - 길이: 2195 mm
기본 벽:WA211-시멘트벽돌(일반) 벽 (0.5B) 90mm:5356040 | 지상 6층 | 394.8 |  |  | 새 구성 | 벽 | CW112-스테인리스 스틸 커튼월 | 7675291 | 커튼월 | 커튼월: CW112-스테인리스 스틸 커튼월 | 3.6864 | CW112-스테인리스 스틸 커튼월 | 2 | ID 데이터 - 마크: 29; 해설: SSD; 구속조건 - 매스와 관련됨: no; 룸 경계: yes; 벽 베이스가 부착됩니다.: no; 상단이 부착됩니다.: no; 베이스 구속조건: 지상 6층; 상단 구속조건: 상위 레벨: 지상 7층; 미연결 높이: 2620 mm; 베이스 간격띄우기: 80 mm; 상단 간격띄우기: -1400 mm; 구조 - 구조: no; 구조적 용도: 비교좌장치; 단면형상 정의 - 단면형상: 수직; 수직 그리드 - 각도: 0 deg; 간격띄우기: 0 mm; 맞춤: 시작; 번호: 4; sets with these values: 2; 치수 - 길이: 2640 mm; BaseQuantities - Area: 3.6864 m2
기본 벽:WA211-시멘트벽돌(일반) 벽 (0.5B) 90mm:5356041 | 지상 6층 | 394.8 |  |  | 새 구성 | 벽 | CW112-스테인리스 스틸 커튼월 | 7675291 | 커튼월 | 커튼월: CW112-스테인리스 스틸 커튼월 | 4.2104 | CW112-스테인리스 스틸 커튼월 | 2 | ID 데이터 - 마크: 29; 해설: SSD; 구속조건 - 매스와 관련됨: no; 룸 경계: yes; 벽 베이스가 부착됩니다.: no; 상단이 부착됩니다.: no; 베이스 구속조건: 지상 6층; 상단 구속조건: 상위 레벨: 지상 7층; 미연결 높이: 2620 mm; 베이스 간격띄우기: 80 mm; 상단 간격띄우기: -1400 mm; 구조 - 구조: no; 구조적 용도: 비교좌장치; 단면형상 정의 - 단면형상: 수직; 수직 그리드 - 각도: 0 deg; 간격띄우기: 0 mm; 맞춤: 시작; 번호: 4; sets with these values: 2; 치수 - 길이: 2795 mm; BaseQuantities - Area: 4.2104 m2
기본 벽:WA211-시멘트벽돌(일반) 벽 (0.5B) 90mm:5356252 | 지상 7층 | 394.8 |  |  | 새 구성 | 벽 | CW112-스테인리스 스틸 커튼월 | 7675291 | 커튼월 | 커튼월: CW112-스테인리스 스틸 커튼월 | 3.54125 | CW112-스테인리스 스틸 커튼월 | 2 | ID 데이터 - 마크: 25; 해설: SSD; 구속조건 - 매스와 관련됨: no; 룸 경계: yes; 벽 베이스가 부착됩니다.: no; 상단이 부착됩니다.: no; 베이스 구속조건: 지상 7층; 상단 구속조건: 상위 레벨: 지상 8층; 미연결 높이: 2620 mm; 베이스 간격띄우기: 80 mm; 상단 간격띄우기: -1400 mm; 구조 - 구조: no; 구조적 용도: 비교좌장치; 단면형상 정의 - 단면형상: 수직; 수직 그리드 - 각도: 0 deg; 간격띄우기: 0 mm; 맞춤: 시작; 번호: 4; sets with these values: 2; 치수 - 길이: 2600 mm; BaseQuantities - Area: 3.54125 m2
기본 벽:WA211-시멘트벽돌(일반) 벽 (0.5B) 90mm:5356253 | 지상 7층 | 394.8 |  |  | 새 구성 | 벽 | CW112-스테인리스 스틸 커튼월 | 7675291 | 커튼월 | 커튼월: CW112-스테인리스 스틸 커튼월 | 14.1795 | CW112-스테인리스 스틸 커튼월 | 2 | ID 데이터 - 마크: 26; 해설: SSD; 구속조건 - 매스와 관련됨: no; 룸 경계: yes; 벽 베이스가 부착됩니다.: no; 상단이 부착됩니다.: no; 베이스 구속조건: 지상 7층; 상단 구속조건: 상위 레벨: 지상 8층; 미연결 높이: 2620 mm; 베이스 간격띄우기: 80 mm; 상단 간격띄우기: -1400 mm; 구조 - 구조: no; 구조적 용도: 비교좌장치; 단면형상 정의 - 단면형상: 수직; 수직 그리드 - 각도: 0 deg; 간격띄우기: 0 mm; 맞춤: 시작; 번호: 4; sets with these values: 2; 치수 - 길이: 6600 mm; BaseQuantities - Area: 14.1795 m2
기본 벽:WA211-시멘트벽돌(일반) 벽 (0.5B) 90mm:5356255 | 지상 7층 | 394.8 |  |  | 새 구성 | 벽 | CW112-스테인리스 스틸 커튼월 | 7675291 | 커튼월 | 커튼월: CW112-스테인리스 스틸 커튼월 | 3.55054 | CW112-스테인리스 스틸 커튼월 | 2 | ID 데이터 - 마크: 25; 해설: SSD; 구속조건 - 매스와 관련됨: no; 룸 경계: yes; 벽 베이스가 부착됩니다.: no; 상단이 부착됩니다.: no; 베이스 구속조건: 지상 7층; 상단 구속조건: 상위 레벨: 지상 8층; 미연결 높이: 2620 mm; 베이스 간격띄우기: 80 mm; 상단 간격띄우기: -1400 mm; 구조 - 구조: no; 구조적 용도: 비교좌장치; 단면형상 정의 - 단면형상: 수직; 수직 그리드 - 각도: 0 deg; 간격띄우기: 0 mm; 맞춤: 시작; 번호: 4; sets with these values: 2; 치수 - 길이: 2543.15 mm; BaseQuantities - Area: 3.55054 m2
기본 벽:WA211-시멘트벽돌(일반) 벽 (0.5B) 90mm:5356256 | 지상 7층 | 394.8 |  |  | 새 구성 | 벽 | CW112-스테인리스 스틸 커튼월 | 7675291 | 커튼월 | 커튼월: CW112-스테인리스 스틸 커튼월 | 22.8255 | CW112-스테인리스 스틸 커튼월 | 2 | ID 데이터 - 마크: 28; 해설: SSD; 구속조건 - 매스와 관련됨: no; 룸 경계: yes; 벽 베이스가 부착됩니다.: no; 상단이 부착됩니다.: no; 베이스 구속조건: 지상 7층; 상단 구속조건: 상위 레벨: 지상 8층; 미연결 높이: 2620 mm; 베이스 간격띄우기: 80 mm; 상단 간격띄우기: -1400 mm; 구조 - 구조: no; 구조적 용도: 비교좌장치; 단면형상 정의 - 단면형상: 수직; 수직 그리드 - 각도: 0 deg; 간격띄우기: 0 mm; 맞춤: 시작; 번호: 4; sets with these values: 2; 치수 - 길이: 9900 mm; BaseQuantities - Area: 22.8255 m2
기본 벽:WA211-시멘트벽돌(일반) 벽 (0.5B) 90mm:5356257 | 지상 7층 | 394.8 | 2199.98 | 2620 | 새 구성 | 벽 | CW112-스테인리스 스틸 커튼월 | 7675291 | 커튼월 | 커튼월: CW112-스테인리스 스틸 커튼월 | 5.76396 | CW112-스테인리스 스틸 커튼월 | 2 | ID 데이터 - 마크: 29; 해설: SSD; 구속조건 - 매스와 관련됨: no; 룸 경계: yes; 벽 베이스가 부착됩니다.: no; 상단이 부착됩니다.: no; 베이스 구속조건: 지상 7층; 상단 구속조건: 상위 레벨: 지상 8층; 미연결 높이: 2620 mm; 베이스 간격띄우기: 80 mm; 상단 간격띄우기: -1400 mm; 구조 - 구조: no; 구조적 용도: 비교좌장치; 단면형상 정의 - 단면형상: 수직; 수직 그리드 - 각도: 0 deg; 간격띄우기: 0 mm; 맞춤: 시작; 번호: 4; sets with these values: 2; 치수 - 길이: 2199.98 mm
기본 벽:WA211-시멘트벽돌(일반) 벽 (0.5B) 90mm:5356258 | 지상 7층 | 394.8 |  |  | 새 구성 | 벽 | CW112-스테인리스 스틸 커튼월 | 7675291 | 커튼월 | 커튼월: CW112-스테인리스 스틸 커튼월 | 3.6995 | CW112-스테인리스 스틸 커튼월 | 2 | ID 데이터 - 마크: 29; 해설: SSD; 구속조건 - 매스와 관련됨: no; 룸 경계: yes; 벽 베이스가 부착됩니다.: no; 상단이 부착됩니다.: no; 베이스 구속조건: 지상 7층; 상단 구속조건: 상위 레벨: 지상 8층; 미연결 높이: 2620 mm; 베이스 간격띄우기: 80 mm; 상단 간격띄우기: -1400 mm; 구조 - 구조: no; 구조적 용도: 비교좌장치; 단면형상 정의 - 단면형상: 수직; 수직 그리드 - 각도: 0 deg; 간격띄우기: 0 mm; 맞춤: 시작; 번호: 4; sets with these values: 2; 치수 - 길이: 2645 mm; BaseQuantities - Area: 3.6995 m2
기본 벽:WA211-시멘트벽돌(일반) 벽 (0.5B) 90mm:5356259 | 지상 7층 | 394.8 |  |  | 새 구성 | 벽 | CW112-스테인리스 스틸 커튼월 | 7675291 | 커튼월 | 커튼월: CW112-스테인리스 스틸 커튼월 | 4.2104 | CW112-스테인리스 스틸 커튼월 | 2 | ID 데이터 - 마크: 29; 해설: SSD; 구속조건 - 매스와 관련됨: no; 룸 경계: yes; 벽 베이스가 부착됩니다.: no; 상단이 부착됩니다.: no; 베이스 구속조건: 지상 7층; 상단 구속조건: 상위 레벨: 지상 8층; 미연결 높이: 2620 mm; 베이스 간격띄우기: 80 mm; 상단 간격띄우기: -1400 mm; 구조 - 구조: no; 구조적 용도: 비교좌장치; 단면형상 정의 - 단면형상: 수직; 수직 그리드 - 각도: 0 deg; 간격띄우기: 0 mm; 맞춤: 시작; 번호: 4; sets with these values: 2; 치수 - 길이: 2795 mm; BaseQuantities - Area: 4.2104 m2
기본 벽:WA211-시멘트벽돌(일반) 벽 (0.5B) 90mm:5356470 | 지상 8층 | 394.8 |  |  | 새 구성 | 벽 | CW112-스테인리스 스틸 커튼월 | 7675291 | 커튼월 | 커튼월: CW112-스테인리스 스틸 커튼월 | 3.54127 | CW112-스테인리스 스틸 커튼월 | 2 | ID 데이터 - 마크: 25; 해설: SSD; 구속조건 - 매스와 관련됨: no; 룸 경계: yes; 벽 베이스가 부착됩니다.: no; 상단이 부착됩니다.: no; 베이스 구속조건: 지상 8층; 상단 구속조건: 상위 레벨: 지상 9층; 미연결 높이: 2620 mm; 베이스 간격띄우기: 80 mm; 상단 간격띄우기: -1400 mm; 구조 - 구조: no; 구조적 용도: 비교좌장치; 단면형상 정의 - 단면형상: 수직; 수직 그리드 - 각도: 0 deg; 간격띄우기: 0 mm; 맞춤: 시작; 번호: 4; sets with these values: 2; 치수 - 길이: 2600.01 mm; BaseQuantities - Area: 3.54127 m2
기본 벽:WA211-시멘트벽돌(일반) 벽 (0.5B) 90mm:5356471 | 지상 8층 | 394.8 |  |  | 새 구성 | 벽 | CW112-스테인리스 스틸 커튼월 | 7675291 | 커튼월 | 커튼월: CW112-스테인리스 스틸 커튼월 | 14.7036 | CW112-스테인리스 스틸 커튼월 | 2 | ID 데이터 - 마크: 26; 해설: SSD; 구속조건 - 매스와 관련됨: no; 룸 경계: yes; 벽 베이스가 부착됩니다.: no; 상단이 부착됩니다.: no; 베이스 구속조건: 지상 8층; 상단 구속조건: 상위 레벨: 지상 9층; 미연결 높이: 2620 mm; 베이스 간격띄우기: 80 mm; 상단 간격띄우기: -1400 mm; 구조 - 구조: no; 구조적 용도: 비교좌장치; 단면형상 정의 - 단면형상: 수직; 수직 그리드 - 각도: 0 deg; 간격띄우기: 0 mm; 맞춤: 시작; 번호: 4; sets with these values: 2; 치수 - 길이: 6800.03 mm; BaseQuantities - Area: 14.7036 m2
기본 벽:WA211-시멘트벽돌(일반) 벽 (0.5B) 90mm:5356473 | 지상 8층 | 394.8 |  |  | 새 구성 | 벽 | CW112-스테인리스 스틸 커튼월 | 7675291 | 커튼월 | 커튼월: CW112-스테인리스 스틸 커튼월 | 3.43755 | CW112-스테인리스 스틸 커튼월 | 2 | ID 데이터 - 마크: 25; 해설: SSD; 구속조건 - 매스와 관련됨: no; 룸 경계: yes; 벽 베이스가 부착됩니다.: no; 상단이 부착됩니다.: no; 베이스 구속조건: 지상 8층; 상단 구속조건: 상위 레벨: 지상 9층; 미연결 높이: 2620 mm; 베이스 간격띄우기: 80 mm; 상단 간격띄우기: -1400 mm; 구조 - 구조: no; 구조적 용도: 비교좌장치; 단면형상 정의 - 단면형상: 수직; 수직 그리드 - 각도: 0 deg; 간격띄우기: 0 mm; 맞춤: 시작; 번호: 4; sets with these values: 2; 치수 - 길이: 2500.02 mm; BaseQuantities - Area: 3.43755 m2
기본 벽:WA211-시멘트벽돌(일반) 벽 (0.5B) 90mm:5356474 | 지상 8층 | 394.8 |  |  | 새 구성 | 벽 | CW112-스테인리스 스틸 커튼월 | 7675291 | 커튼월 | 커튼월: CW112-스테인리스 스틸 커튼월 | 23.0875 | CW112-스테인리스 스틸 커튼월 | 2 | ID 데이터 - 마크: 28; 해설: SSD; 구속조건 - 매스와 관련됨: no; 룸 경계: yes; 벽 베이스가 부착됩니다.: no; 상단이 부착됩니다.: no; 베이스 구속조건: 지상 8층; 상단 구속조건: 상위 레벨: 지상 9층; 미연결 높이: 2620 mm; 베이스 간격띄우기: 80 mm; 상단 간격띄우기: -1400 mm; 구조 - 구조: no; 구조적 용도: 비교좌장치; 단면형상 정의 - 단면형상: 수직; 수직 그리드 - 각도: 0 deg; 간격띄우기: 0 mm; 맞춤: 시작; 번호: 4; sets with these values: 2; 치수 - 길이: 10000 mm; BaseQuantities - Area: 23.0875 m2
기본 벽:WA211-시멘트벽돌(일반) 벽 (0.5B) 90mm:5356475 | 지상 8층 | 394.8 | 2295.02 | 2620 | 새 구성 | 벽 | CW112-스테인리스 스틸 커튼월 | 7675291 | 커튼월 | 커튼월: CW112-스테인리스 스틸 커튼월 | 6.01295 | CW112-스테인리스 스틸 커튼월 | 2 | ID 데이터 - 마크: 29; 해설: SSD; 구속조건 - 매스와 관련됨: no; 룸 경계: yes; 벽 베이스가 부착됩니다.: no; 상단이 부착됩니다.: no; 베이스 구속조건: 지상 8층; 상단 구속조건: 상위 레벨: 지상 9층; 미연결 높이: 2620 mm; 베이스 간격띄우기: 80 mm; 상단 간격띄우기: -1400 mm; 구조 - 구조: no; 구조적 용도: 비교좌장치; 단면형상 정의 - 단면형상: 수직; 수직 그리드 - 각도: 0 deg; 간격띄우기: 0 mm; 맞춤: 시작; 번호: 4; sets with these values: 2; 치수 - 길이: 2295.02 mm
기본 벽:WA211-시멘트벽돌(일반) 벽 (0.5B) 90mm:5356476 | 지상 8층 | 394.8 |  |  | 새 구성 | 벽 | CW112-스테인리스 스틸 커튼월 | 7675291 | 커튼월 | 커튼월: CW112-스테인리스 스틸 커튼월 | 3.6733 | CW112-스테인리스 스틸 커튼월 | 2 | ID 데이터 - 마크: 29; 해설: SSD; 구속조건 - 매스와 관련됨: no; 룸 경계: yes; 벽 베이스가 부착됩니다.: no; 상단이 부착됩니다.: no; 베이스 구속조건: 지상 8층; 상단 구속조건: 상위 레벨: 지상 9층; 미연결 높이: 2620 mm; 베이스 간격띄우기: 80 mm; 상단 간격띄우기: -1400 mm; 구조 - 구조: no; 구조적 용도: 비교좌장치; 단면형상 정의 - 단면형상: 수직; 수직 그리드 - 각도: 0 deg; 간격띄우기: 0 mm; 맞춤: 시작; 번호: 4; sets with these values: 2; 치수 - 길이: 2635 mm; BaseQuantities - Area: 3.6733 m2
기본 벽:WA211-시멘트벽돌(일반) 벽 (0.5B) 90mm:5356477 | 지상 8층 | 394.8 |  |  | 새 구성 | 벽 | CW112-스테인리스 스틸 커튼월 | 7675291 | 커튼월 | 커튼월: CW112-스테인리스 스틸 커튼월 | 4.2104 | CW112-스테인리스 스틸 커튼월 | 2 | ID 데이터 - 마크: 29; 해설: SSD; 구속조건 - 매스와 관련됨: no; 룸 경계: yes; 벽 베이스가 부착됩니다.: no; 상단이 부착됩니다.: no; 베이스 구속조건: 지상 8층; 상단 구속조건: 상위 레벨: 지상 9층; 미연결 높이: 2620 mm; 베이스 간격띄우기: 80 mm; 상단 간격띄우기: -1400 mm; 구조 - 구조: no; 구조적 용도: 비교좌장치; 단면형상 정의 - 단면형상: 수직; 수직 그리드 - 각도: 0 deg; 간격띄우기: 0 mm; 맞춤: 시작; 번호: 4; sets with these values: 2; 치수 - 길이: 2795 mm; BaseQuantities - Area: 4.2104 m2
기본 벽:WA211-시멘트벽돌(일반) 벽 (0.5B) 90mm:5356689 | 지상 9층 | 394.8 |  |  | 새 구성 | 벽 | CW112-스테인리스 스틸 커튼월 | 7675291 | 커튼월 | 커튼월: CW112-스테인리스 스틸 커튼월 | 17.4236 | CW112-스테인리스 스틸 커튼월 | 2 | ID 데이터 - 마크: 26; 해설: SSD; 구속조건 - 매스와 관련됨: no; 룸 경계: yes; 벽 베이스가 부착됩니다.: no; 상단이 부착됩니다.: no; 베이스 구속조건: 지상 9층; 상단 구속조건: 상위 레벨: 지상 10층; 미연결 높이: 3020 mm; 베이스 간격띄우기: 80 mm; 상단 간격띄우기: -1400 mm; 구조 - 구조: no; 구조적 용도: 비교좌장치; 단면형상 정의 - 단면형상: 수직; 수직 그리드 - 각도: 0 deg; 간격띄우기: 0 mm; 맞춤: 시작; 번호: 4; sets with these values: 2; 치수 - 길이: 6800.03 mm; BaseQuantities - Area: 17.4236 m2
기본 벽:WA211-시멘트벽돌(일반) 벽 (0.5B) 90mm:5356691 | 지상 9층 | 394.8 |  |  | 새 구성 | 벽 | CW112-스테인리스 스틸 커튼월 | 7675291 | 커튼월 | 커튼월: CW112-스테인리스 스틸 커튼월 | 4.4375 | CW112-스테인리스 스틸 커튼월 | 2 | ID 데이터 - 마크: 25; 해설: SSD; 구속조건 - 매스와 관련됨: no; 룸 경계: yes; 벽 베이스가 부착됩니다.: no; 상단이 부착됩니다.: no; 베이스 구속조건: 지상 9층; 상단 구속조건: 상위 레벨: 지상 10층; 미연결 높이: 3020 mm; 베이스 간격띄우기: 80 mm; 상단 간격띄우기: -1400 mm; 구조 - 구조: no; 구조적 용도: 비교좌장치; 단면형상 정의 - 단면형상: 수직; 수직 그리드 - 각도: 0 deg; 간격띄우기: 0 mm; 맞춤: 시작; 번호: 4; sets with these values: 2; 치수 - 길이: 2500 mm; BaseQuantities - Area: 4.4375 m2
기본 벽:WA211-시멘트벽돌(일반) 벽 (0.5B) 90mm:5356692 | 지상 9층 | 394.8 |  |  | 새 구성 | 벽 | CW112-스테인리스 스틸 커튼월 | 7675291 | 커튼월 | 커튼월: CW112-스테인리스 스틸 커튼월 | 27.0875 | CW112-스테인리스 스틸 커튼월 | 2 | ID 데이터 - 마크: 28; 해설: SSD; 구속조건 - 매스와 관련됨: no; 룸 경계: yes; 벽 베이스가 부착됩니다.: no; 상단이 부착됩니다.: no; 베이스 구속조건: 지상 9층; 상단 구속조건: 상위 레벨: 지상 10층; 미연결 높이: 3020 mm; 베이스 간격띄우기: 80 mm; 상단 간격띄우기: -1400 mm; 구조 - 구조: no; 구조적 용도: 비교좌장치; 단면형상 정의 - 단면형상: 수직; 수직 그리드 - 각도: 0 deg; 간격띄우기: 0 mm; 맞춤: 시작; 번호: 4; sets with these values: 2; 치수 - 길이: 10000 mm; BaseQuantities - Area: 27.0875 m2
기본 벽:WA211-시멘트벽돌(일반) 벽 (0.5B) 90mm:5356693 | 지상 9층 | 394.8 | 2300 | 3020 | 새 구성 | 벽 | CW112-스테인리스 스틸 커튼월 | 7675291 | 커튼월 | 커튼월: CW112-스테인리스 스틸 커튼월 | 6.946 | CW112-스테인리스 스틸 커튼월 | 2 | ID 데이터 - 마크: 29; 해설: SSD; 구속조건 - 매스와 관련됨: no; 룸 경계: yes; 벽 베이스가 부착됩니다.: no; 상단이 부착됩니다.: no; 베이스 구속조건: 지상 9층; 상단 구속조건: 상위 레벨: 지상 10층; 미연결 높이: 3020 mm; 베이스 간격띄우기: 80 mm; 상단 간격띄우기: -1400 mm; 구조 - 구조: no; 구조적 용도: 비교좌장치; 단면형상 정의 - 단면형상: 수직; 수직 그리드 - 각도: 0 deg; 간격띄우기: 0 mm; 맞춤: 시작; 번호: 4; sets with these values: 2; 치수 - 길이: 2300 mm
기본 벽:WA211-시멘트벽돌(일반) 벽 (0.5B) 90mm:5356694 | 지상 9층 | 394.8 |  |  | 새 구성 | 벽 | CW112-스테인리스 스틸 커튼월 | 7675291 | 커튼월 | 커튼월: CW112-스테인리스 스틸 커튼월 | 5.0113 | CW112-스테인리스 스틸 커튼월 | 2 | ID 데이터 - 마크: 29; 해설: SSD; 구속조건 - 매스와 관련됨: no; 룸 경계: yes; 벽 베이스가 부착됩니다.: no; 상단이 부착됩니다.: no; 베이스 구속조건: 지상 9층; 상단 구속조건: 상위 레벨: 지상 10층; 미연결 높이: 3020 mm; 베이스 간격띄우기: 80 mm; 상단 간격띄우기: -1400 mm; 구조 - 구조: no; 구조적 용도: 비교좌장치; 단면형상 정의 - 단면형상: 수직; 수직 그리드 - 각도: 0 deg; 간격띄우기: 0 mm; 맞춤: 시작; 번호: 4; sets with these values: 2; 치수 - 길이: 2690 mm; BaseQuantities - Area: 5.0113 m2
기본 벽:WA211-시멘트벽돌(일반) 벽 (0.5B) 90mm:5356695 | 지상 9층 | 394.8 |  |  | 새 구성 | 벽 | CW112-스테인리스 스틸 커튼월 | 7675291 | 커튼월 | 커튼월: CW112-스테인리스 스틸 커튼월 | 5.3284 | CW112-스테인리스 스틸 커튼월 | 2 | ID 데이터 - 마크: 29; 해설: SSD; 구속조건 - 매스와 관련됨: no; 룸 경계: yes; 벽 베이스가 부착됩니다.: no; 상단이 부착됩니다.: no; 베이스 구속조건: 지상 9층; 상단 구속조건: 상위 레벨: 지상 10층; 미연결 높이: 3020 mm; 베이스 간격띄우기: 80 mm; 상단 간격띄우기: -1400 mm; 구조 - 구조: no; 구조적 용도: 비교좌장치; 단면형상 정의 - 단면형상: 수직; 수직 그리드 - 각도: 0 deg; 간격띄우기: 0 mm; 맞춤: 시작; 번호: 4; sets with these values: 2; 치수 - 길이: 2795 mm; BaseQuantities - Area: 5.3284 m2
기본 벽:(복합)WA211+A1-32-06A-시멘트벽돌(일반)+수성:5356907 | 지상 10층 | 430.8 |  |  | 새 구성 | 벽 | CW112-스테인리스 스틸 커튼월 | 7675291 | 커튼월 | 커튼월: CW112-스테인리스 스틸 커튼월 | 20.4715 | CW112-스테인리스 스틸 커튼월 | 2 | ID 데이터 - 마크: 26; 해설: SSD; 구속조건 - 매스와 관련됨: no; 룸 경계: yes; 벽 베이스가 부착됩니다.: no; 상단이 부착됩니다.: no; 베이스 구속조건: 지상 10층; 상단 구속조건: 상위 레벨: 옥탑층; 미연결 높이: 3520 mm; 베이스 간격띄우기: 80 mm; 상단 간격띄우기: -1400 mm; 구조 - 구조: no; 구조적 용도: 비교좌장치; 단면형상 정의 - 단면형상: 수직; 수직 그리드 - 각도: 0 deg; 간격띄우기: 0 mm; 맞춤: 시작; 번호: 4; sets with these values: 2; 치수 - 길이: 6700 mm; BaseQuantities - Area: 20.4715 m2
기본 벽:(복합)WA211+A1-32-06A-시멘트벽돌(일반)+수성:5356908 | 지상 10층 | 430.8 |  |  | 새 구성 | 벽 | CW112-스테인리스 스틸 커튼월 | 7675291 | 커튼월 | 커튼월: CW112-스테인리스 스틸 커튼월 | 19.765 | CW112-스테인리스 스틸 커튼월 | 2 | ID 데이터 - 마크: 27; 해설: SSD; 구속조건 - 매스와 관련됨: no; 룸 경계: yes; 벽 베이스가 부착됩니다.: no; 상단이 부착됩니다.: no; 베이스 구속조건: 지상 10층; 상단 구속조건: 상위 레벨: 옥탑층; 미연결 높이: 3520 mm; 베이스 간격띄우기: 80 mm; 상단 간격띄우기: -1400 mm; 구조 - 구조: no; 구조적 용도: 비교좌장치; 단면형상 정의 - 단면형상: 수직; 수직 그리드 - 각도: 0 deg; 간격띄우기: 0 mm; 맞춤: 시작; 번호: 4; sets with these values: 2; 치수 - 길이: 6549.28 mm; BaseQuantities - Area: 19.765 m2
기본 벽:(복합)WA211+A1-32-06A-시멘트벽돌(일반)+수성:5356909 | 지상 10층 | 430.8 |  |  | 새 구성 | 벽 | CW112-스테인리스 스틸 커튼월 | 7675291 | 커튼월 | 커튼월: CW112-스테인리스 스틸 커튼월 | 5.6875 | CW112-스테인리스 스틸 커튼월 | 2 | ID 데이터 - 마크: 25; 해설: SSD; 구속조건 - 매스와 관련됨: no; 룸 경계: yes; 벽 베이스가 부착됩니다.: no; 상단이 부착됩니다.: no; 베이스 구속조건: 지상 10층; 상단 구속조건: 상위 레벨: 옥탑층; 미연결 높이: 3520 mm; 베이스 간격띄우기: 80 mm; 상단 간격띄우기: -1400 mm; 구조 - 구조: no; 구조적 용도: 비교좌장치; 단면형상 정의 - 단면형상: 수직; 수직 그리드 - 각도: 0 deg; 간격띄우기: 0 mm; 맞춤: 시작; 번호: 4; sets with these values: 2; 치수 - 길이: 2500 mm; BaseQuantities - Area: 5.6875 m2
기본 벽:(복합)WA211+A1-32-06A-시멘트벽돌(일반)+수성:5356910 | 지상 10층 | 430.8 |  |  | 새 구성 | 벽 | CW112-스테인리스 스틸 커튼월 | 7675291 | 커튼월 | 커튼월: CW112-스테인리스 스틸 커튼월 | 32.0875 | CW112-스테인리스 스틸 커튼월 | 2 | ID 데이터 - 마크: 28; 해설: SSD; 구속조건 - 매스와 관련됨: no; 룸 경계: yes; 벽 베이스가 부착됩니다.: no; 상단이 부착됩니다.: no; 베이스 구속조건: 지상 10층; 상단 구속조건: 상위 레벨: 옥탑층; 미연결 높이: 3520 mm; 베이스 간격띄우기: 80 mm; 상단 간격띄우기: -1400 mm; 구조 - 구조: no; 구조적 용도: 비교좌장치; 단면형상 정의 - 단면형상: 수직; 수직 그리드 - 각도: 0 deg; 간격띄우기: 0 mm; 맞춤: 시작; 번호: 4; sets with these values: 2; 치수 - 길이: 10000 mm; BaseQuantities - Area: 32.0875 m2
기본 벽:(복합)WA211+A1-32-06A-시멘트벽돌(일반)+수성:5356911 | 지상 10층 | 430.8 | 2300 | 3520 | 새 구성 | 벽 | CW112-스테인리스 스틸 커튼월 | 7675291 | 커튼월 | 커튼월: CW112-스테인리스 스틸 커튼월 | 8.096 | CW112-스테인리스 스틸 커튼월 | 2 | ID 데이터 - 마크: 29; 해설: SSD; 구속조건 - 매스와 관련됨: no; 룸 경계: yes; 벽 베이스가 부착됩니다.: no; 상단이 부착됩니다.: no; 베이스 구속조건: 지상 10층; 상단 구속조건: 상위 레벨: 옥탑층; 미연결 높이: 3520 mm; 베이스 간격띄우기: 80 mm; 상단 간격띄우기: -1400 mm; 구조 - 구조: no; 구조적 용도: 비교좌장치; 단면형상 정의 - 단면형상: 수직; 수직 그리드 - 각도: 0 deg; 간격띄우기: 0 mm; 맞춤: 시작; 번호: 4; sets with these values: 2; 치수 - 길이: 2300 mm
기본 벽:(복합)WA211+A1-32-06A-시멘트벽돌(일반)+수성:5356912 | 지상 10층 | 430.8 |  |  | 새 구성 | 벽 | CW112-스테인리스 스틸 커튼월 | 7675291 | 커튼월 | 커튼월: CW112-스테인리스 스틸 커튼월 | 6.05698 | CW112-스테인리스 스틸 커튼월 | 2 | ID 데이터 - 마크: 29; 해설: SSD; 구속조건 - 매스와 관련됨: no; 룸 경계: yes; 벽 베이스가 부착됩니다.: no; 상단이 부착됩니다.: no; 베이스 구속조건: 지상 10층; 상단 구속조건: 상위 레벨: 옥탑층; 미연결 높이: 3520 mm; 베이스 간격띄우기: 80 mm; 상단 간격띄우기: -1400 mm; 구조 - 구조: no; 구조적 용도: 비교좌장치; 단면형상 정의 - 단면형상: 수직; 수직 그리드 - 각도: 0 deg; 간격띄우기: 0 mm; 맞춤: 시작; 번호: 4; sets with these values: 2; 치수 - 길이: 2649.97 mm; BaseQuantities - Area: 6.05698 m2
기본 벽:(복합)WA211+A1-32-06A-시멘트벽돌(일반)+수성:5356913 | 지상 10층 | 430.8 |  |  | 새 구성 | 벽 | CW112-스테인리스 스틸 커튼월 | 7675291 | 커튼월 | 커튼월: CW112-스테인리스 스틸 커튼월 | 6.74353 | CW112-스테인리스 스틸 커튼월 | 2 | ID 데이터 - 마크: 29; 해설: SSD; 구속조건 - 매스와 관련됨: no; 룸 경계: yes; 벽 베이스가 부착됩니다.: no; 상단이 부착됩니다.: no; 베이스 구속조건: 지상 10층; 상단 구속조건: 상위 레벨: 옥탑층; 미연결 높이: 3520 mm; 베이스 간격띄우기: 80 mm; 상단 간격띄우기: -1400 mm; 구조 - 구조: no; 구조적 용도: 비교좌장치; 단면형상 정의 - 단면형상: 수직; 수직 그리드 - 각도: 0 deg; 간격띄우기: 0 mm; 맞춤: 시작; 번호: 4; sets with these values: 2; 치수 - 길이: 2800.01 mm; BaseQuantities - Area: 6.74353 m2
기본 벽:WA211-시멘트벽돌(일반) 벽 (0.5B) 90mm:5367175 | 지상 3층 | 394.8 | 6500.03 | 2620 | 새 구성 | 벽 | CW112-스테인리스 스틸 커튼월 | 7675291 | 커튼월 | 커튼월: CW112-스테인리스 스틸 커튼월 | 17.0301 | CW112-스테인리스 스틸 커튼월 | 2 | ID 데이터 - 마크: 27; 해설: SSD; 구속조건 - 매스와 관련됨: no; 룸 경계: yes; 벽 베이스가 부착됩니다.: no; 상단이 부착됩니다.: no; 베이스 구속조건: 지상 3층; 상단 구속조건: 상위 레벨: 지상 4층; 미연결 높이: 2620 mm; 베이스 간격띄우기: 80 mm; 상단 간격띄우기: -1400 mm; 구조 - 구조: no; 구조적 용도: 비교좌장치; 단면형상 정의 - 단면형상: 수직; 수직 그리드 - 각도: 0 deg; 간격띄우기: 0 mm; 맞춤: 시작; 번호: 4; sets with these values: 2; 치수 - 길이: 6500.03 mm
기본 벽:WA211-시멘트벽돌(일반) 벽 (0.5B) 90mm:5367175 | 지상 3층 | 394.8 | 2750 | 2620 | 새 구성 | 벽 | CW112-스테인리스 스틸 커튼월 | 7675291 | 커튼월 | 커튼월: CW112-스테인리스 스틸 커튼월 | 7.205 | CW112-스테인리스 스틸 커튼월 | 2 | ID 데이터 - 마크: 26; 해설: SSD; 구속조건 - 매스와 관련됨: no; 룸 경계: yes; 벽 베이스가 부착됩니다.: no; 상단이 부착됩니다.: no; 베이스 구속조건: 지상 3층; 상단 구속조건: 상위 레벨: 지상 4층; 미연결 높이: 2620 mm; 베이스 간격띄우기: 80 mm; 상단 간격띄우기: -1400 mm; 구조 - 구조: no; 구조적 용도: 비교좌장치; 단면형상 정의 - 단면형상: 수직; 수직 그리드 - 각도: 0 deg; 간격띄우기: 0 mm; 맞춤: 시작; 번호: 4; sets with these values: 2; 치수 - 길이: 2850 mm
기본 벽:WA211-시멘트벽돌(일반) 벽 (0.5B) 90mm:5367175 | 지상 3층 | 394.8 | 6600 | 2620 | 새 구성 | 벽 | CW112-스테인리스 스틸 커튼월 | 7675291 | 커튼월 | 커튼월: CW112-스테인리스 스틸 커튼월 | 17.292 | CW112-스테인리스 스틸 커튼월 | 2 | ID 데이터 - 마크: 26; 해설: SSD; 구속조건 - 매스와 관련됨: no; 룸 경계: yes; 벽 베이스가 부착됩니다.: no; 상단이 부착됩니다.: no; 베이스 구속조건: 지상 3층; 상단 구속조건: 상위 레벨: 지상 4층; 미연결 높이: 2620 mm; 베이스 간격띄우기: 80 mm; 상단 간격띄우기: -1400 mm; 구조 - 구조: no; 구조적 용도: 비교좌장치; 단면형상 정의 - 단면형상: 수직; 수직 그리드 - 각도: 0 deg; 간격띄우기: 0 mm; 맞춤: 시작; 번호: 4; sets with these values: 2; 치수 - 길이: 6600 mm
기본 벽:WA211-시멘트벽돌(일반) 벽 (0.5B) 90mm:5369281 | 지상 2층 | 394.8 | 6500 | 3020 | 새 구성 | 벽 | CW112-스테인리스 스틸 커튼월 | 7675291 | 커튼월 | 커튼월: CW112-스테인리스 스틸 커튼월 | 19.63 | CW112-스테인리스 스틸 커튼월 | 2 | ID 데이터 - 마크: 27; 해설: SSD; 구속조건 - 매스와 관련됨: no; 룸 경계: yes; 벽 베이스가 부착됩니다.: no; 상단이 부착됩니다.: no; 베이스 구속조건: 지상 2층; 상단 구속조건: 상위 레벨: 지상 3층; 미연결 높이: 3020 mm; 베이스 간격띄우기: 80 mm; 상단 간격띄우기: -1400 mm; 구조 - 구조: no; 구조적 용도: 비교좌장치; 단면형상 정의 - 단면형상: 수직; 수직 그리드 - 각도: 0 deg; 간격띄우기: 0 mm; 맞춤: 시작; 번호: 4; sets with these values: 2; 치수 - 길이: 6500 mm
기본 벽:WA211-시멘트벽돌(일반) 벽 (0.5B) 90mm:5369281 | 지상 2층 | 394.8 | 2750 | 3020 | 새 구성 | 벽 | CW112-스테인리스 스틸 커튼월 | 7675291 | 커튼월 | 커튼월: CW112-스테인리스 스틸 커튼월 | 8.305 | CW112-스테인리스 스틸 커튼월 | 2 | ID 데이터 - 마크: 26; 해설: SSD; 구속조건 - 매스와 관련됨: no; 룸 경계: yes; 벽 베이스가 부착됩니다.: no; 상단이 부착됩니다.: no; 베이스 구속조건: 지상 2층; 상단 구속조건: 상위 레벨: 지상 3층; 미연결 높이: 3020 mm; 베이스 간격띄우기: 80 mm; 상단 간격띄우기: -1400 mm; 구조 - 구조: no; 구조적 용도: 비교좌장치; 단면형상 정의 - 단면형상: 수직; 수직 그리드 - 각도: 0 deg; 간격띄우기: 0 mm; 맞춤: 시작; 번호: 4; sets with these values: 2; 치수 - 길이: 2850 mm
기본 벽:WA211-시멘트벽돌(일반) 벽 (0.5B) 90mm:5369281 | 지상 2층 | 394.8 | 6600 | 3020 | 새 구성 | 벽 | CW112-스테인리스 스틸 커튼월 | 7675291 | 커튼월 | 커튼월: CW112-스테인리스 스틸 커튼월 | 19.932 | CW112-스테인리스 스틸 커튼월 | 2 | ID 데이터 - 마크: 26; 해설: SSD; 구속조건 - 매스와 관련됨: no; 룸 경계: yes; 벽 베이스가 부착됩니다.: no; 상단이 부착됩니다.: no; 베이스 구속조건: 지상 2층; 상단 구속조건: 상위 레벨: 지상 3층; 미연결 높이: 3020 mm; 베이스 간격띄우기: 80 mm; 상단 간격띄우기: -1400 mm; 구조 - 구조: no; 구조적 용도: 비교좌장치; 단면형상 정의 - 단면형상: 수직; 수직 그리드 - 각도: 0 deg; 간격띄우기: 0 mm; 맞춤: 시작; 번호: 4; sets with these values: 2; 치수 - 길이: 6600 mm
기본 벽:WA111-철근콘크리트구조 벽 125mm_W3:5381982 | 지상 2층 | 429.8 | 7210 | 3120 | 새 구성 | 벽 | CW112-스테인리스 스틸 커튼월 | 7675291 | 커튼월 | 커튼월: CW112-스테인리스 스틸 커튼월 | 22.4952 | CW112-스테인리스 스틸 커튼월 | 2 | ID 데이터 - 마크: 5; 해설: AW; 구속조건 - 매스와 관련됨: no; 룸 경계: yes; 벽 베이스가 부착됩니다.: no; 상단이 부착됩니다.: no; 베이스 구속조건: 지상 2층; 상단 구속조건: 상위 레벨: 지상 3층; 미연결 높이: 3120 mm; 베이스 간격띄우기: 80 mm; 상단 간격띄우기: -1300 mm; 구조 - 구조: no; 구조적 용도: 비교좌장치; 단면형상 정의 - 단면형상: 수직; 수직 그리드 - 각도: 0 deg; 간격띄우기: 0 mm; 맞춤: 시작; 번호: 4; sets with these values: 2; 치수 - 길이: 7210 mm
기본 벽:WA111-철근콘크리트구조 벽 125mm_W3:5382011 | 지상 2층 | 429.8 | 3120 | 6600 | 새 구성 | 벽 | CW112-스테인리스 스틸 커튼월 | 7675291 | 커튼월 | 커튼월: CW112-스테인리스 스틸 커튼월 | 20.592 | CW112-스테인리스 스틸 커튼월 | 2 | ID 데이터 - 마크: 6; 해설: AW; 구속조건 - 매스와 관련됨: no; 룸 경계: yes; 벽 베이스가 부착됩니다.: no; 상단이 부착됩니다.: no; 베이스 구속조건: 지상 2층; 상단 구속조건: 상위 레벨: 지상 3층; 미연결 높이: 3120 mm; 베이스 간격띄우기: 80 mm; 상단 간격띄우기: -1300 mm; 구조 - 구조: no; 구조적 용도: 비교좌장치; 단면형상 정의 - 단면형상: 수직; 수직 그리드 - 각도: 0 deg; 간격띄우기: 0 mm; 맞춤: 시작; 번호: 4; sets with these values: 2; 치수 - 길이: 6600 mm
기본 벽:WA111-철근콘크리트구조 벽 125mm_W3:5382021 | 지상 2층 | 429.8 | 6500 | 3120 | 새 구성 | 벽 | CW112-스테인리스 스틸 커튼월 | 7675291 | 커튼월 | 커튼월: CW112-스테인리스 스틸 커튼월 | 20.28 | CW112-스테인리스 스틸 커튼월 | 2 | ID 데이터 - 마크: 7; 해설: AW; 구속조건 - 매스와 관련됨: no; 룸 경계: yes; 벽 베이스가 부착됩니다.: no; 상단이 부착됩니다.: no; 베이스 구속조건: 지상 2층; 상단 구속조건: 상위 레벨: 지상 3층; 미연결 높이: 3120 mm; 베이스 간격띄우기: 80 mm; 상단 간격띄우기: -1300 mm; 구조 - 구조: no; 구조적 용도: 비교좌장치; 단면형상 정의 - 단면형상: 수직; 수직 그리드 - 각도: 0 deg; 간격띄우기: 0 mm; 맞춤: 시작; 번호: 4; sets with these values: 2; 치수 - 길이: 6500 mm
기본 벽:WA111-철근콘크리트구조 벽 125mm_W3:5382032 | 지상 2층 | 429.8 | 3120 | 5357 | 새 구성 | 벽 | CW112-스테인리스 스틸 커튼월 | 7675291 | 커튼월 | 커튼월: CW112-스테인리스 스틸 커튼월 | 16.7138 | CW112-스테인리스 스틸 커튼월 | 2 | ID 데이터 - 마크: 8; 해설: AW; 구속조건 - 매스와 관련됨: no; 룸 경계: yes; 벽 베이스가 부착됩니다.: no; 상단이 부착됩니다.: no; 베이스 구속조건: 지상 2층; 상단 구속조건: 상위 레벨: 지상 3층; 미연결 높이: 3120 mm; 베이스 간격띄우기: 80 mm; 상단 간격띄우기: -1300 mm; 구조 - 구조: no; 구조적 용도: 비교좌장치; 단면형상 정의 - 단면형상: 수직; 수직 그리드 - 각도: 0 deg; 간격띄우기: 0 mm; 맞춤: 시작; 번호: 4; sets with these values: 2; 치수 - 길이: 5366 mm
기본 벽:WA111-철근콘크리트구조 벽 125mm_W3:5382032 | 지상 2층 | 429.8 | 3120 | 4322.75 | 새 구성 | 벽 | CW112-스테인리스 스틸 커튼월 | 7675291 | 커튼월 | 커튼월: CW112-스테인리스 스틸 커튼월 | 13.487 | CW112-스테인리스 스틸 커튼월 | 2 | ID 데이터 - 마크: 9; 해설: AW; 구속조건 - 매스와 관련됨: no; 룸 경계: yes; 벽 베이스가 부착됩니다.: no; 상단이 부착됩니다.: no; 베이스 구속조건: 지상 2층; 상단 구속조건: 상위 레벨: 지상 3층; 미연결 높이: 3120 mm; 베이스 간격띄우기: 80 mm; 상단 간격띄우기: -1300 mm; 구조 - 구조: no; 구조적 용도: 비교좌장치; 단면형상 정의 - 단면형상: 수직; 수직 그리드 - 각도: 0 deg; 간격띄우기: 0 mm; 맞춤: 시작; 번호: 4; sets with these values: 2; 치수 - 길이: 4322.75 mm
기본 벽:WA111-철근콘크리트구조 벽 125mm_W3:5382043 | 지상 2층 | 429.8 | 3120 | 5432.03 | 새 구성 | 벽 | CW112-스테인리스 스틸 커튼월 | 7675291 | 커튼월 | 커튼월: CW112-스테인리스 스틸 커튼월 | 16.9479 | CW112-스테인리스 스틸 커튼월 | 2 | ID 데이터 - 마크: 10; 해설: AW; 구속조건 - 매스와 관련됨: no; 룸 경계: yes; 벽 베이스가 부착됩니다.: no; 상단이 부착됩니다.: no; 베이스 구속조건: 지상 2층; 상단 구속조건: 상위 레벨: 지상 3층; 미연결 높이: 3120 mm; 베이스 간격띄우기: 80 mm; 상단 간격띄우기: -1300 mm; 구조 - 구조: no; 구조적 용도: 비교좌장치; 단면형상 정의 - 단면형상: 수직; 수직 그리드 - 각도: 0 deg; 간격띄우기: 0 mm; 맞춤: 시작; 번호: 4; sets with these values: 2; 치수 - 길이: 5441.03 mm
기본 벽:WA111-철근콘크리트구조 벽 125mm_W3:5382043 | 지상 2층 | 429.8 | 3120 | 5450.11 | 새 구성 | 벽 | CW112-스테인리스 스틸 커튼월 | 7675291 | 커튼월 | 커튼월: CW112-스테인리스 스틸 커튼월 | 17.0044 | CW112-스테인리스 스틸 커튼월 | 2 | ID 데이터 - 마크: 11; 해설: AW; 구속조건 - 매스와 관련됨: no; 룸 경계: yes; 벽 베이스가 부착됩니다.: no; 상단이 부착됩니다.: no; 베이스 구속조건: 지상 2층; 상단 구속조건: 상위 레벨: 지상 3층; 미연결 높이: 3120 mm; 베이스 간격띄우기: 80 mm; 상단 간격띄우기: -1300 mm; 구조 - 구조: no; 구조적 용도: 비교좌장치; 단면형상 정의 - 단면형상: 수직; 수직 그리드 - 각도: 0 deg; 간격띄우기: 0 mm; 맞춤: 시작; 번호: 4; sets with these values: 2; 치수 - 길이: 5450.11 mm
기본 벽:WA111-철근콘크리트구조 벽 125mm_W3:5382057 | 지상 2층 | 429.8 | 2500 | 3120 | 새 구성 | 벽 | CW112-스테인리스 스틸 커튼월 | 7675291 | 커튼월 | 커튼월: CW112-스테인리스 스틸 커튼월 | 7.8 | CW112-스테인리스 스틸 커튼월 | 2 | ID 데이터 - 마크: 12; 해설: AW; 구속조건 - 매스와 관련됨: no; 룸 경계: yes; 벽 베이스가 부착됩니다.: no; 상단이 부착됩니다.: no; 베이스 구속조건: 지상 2층; 상단 구속조건: 상위 레벨: 지상 3층; 미연결 높이: 3120 mm; 베이스 간격띄우기: 80 mm; 상단 간격띄우기: -1300 mm; 구조 - 구조: no; 구조적 용도: 비교좌장치; 단면형상 정의 - 단면형상: 수직; 수직 그리드 - 각도: 0 deg; 간격띄우기: 0 mm; 맞춤: 시작; 번호: 4; sets with these values: 2; 치수 - 길이: 2500 mm
기본 벽:WA111-철근콘크리트구조 벽 125mm_W3:5382073 | 지상 2층 | 429.8 | 4457.27 | 3120 | 새 구성 | 벽 | CW112-스테인리스 스틸 커튼월 | 7675291 | 커튼월 | 커튼월: CW112-스테인리스 스틸 커튼월 | 13.9067 | CW112-스테인리스 스틸 커튼월 | 2 | ID 데이터 - 마크: 13; 해설: AW; 구속조건 - 매스와 관련됨: no; 룸 경계: yes; 벽 베이스가 부착됩니다.: no; 상단이 부착됩니다.: no; 베이스 구속조건: 지상 2층; 상단 구속조건: 상위 레벨: 지상 3층; 미연결 높이: 3120 mm; 베이스 간격띄우기: 80 mm; 상단 간격띄우기: -1300 mm; 구조 - 구조: no; 구조적 용도: 비교좌장치; 단면형상 정의 - 단면형상: 수직; 수직 그리드 - 각도: 0 deg; 간격띄우기: 0 mm; 맞춤: 시작; 번호: 4; sets with these values: 2; 치수 - 길이: 4466.27 mm
기본 벽:WA111-철근콘크리트구조 벽 125mm_W3:5382073 | 지상 2층 | 429.8 | 4449.82 | 3120 | 새 구성 | 벽 | CW112-스테인리스 스틸 커튼월 | 7675291 | 커튼월 | 커튼월: CW112-스테인리스 스틸 커튼월 | 13.8835 | CW112-스테인리스 스틸 커튼월 | 2 | ID 데이터 - 마크: 14; 해설: AW; 구속조건 - 매스와 관련됨: no; 룸 경계: yes; 벽 베이스가 부착됩니다.: no; 상단이 부착됩니다.: no; 베이스 구속조건: 지상 2층; 상단 구속조건: 상위 레벨: 지상 3층; 미연결 높이: 3120 mm; 베이스 간격띄우기: 80 mm; 상단 간격띄우기: -1300 mm; 구조 - 구조: no; 구조적 용도: 비교좌장치; 단면형상 정의 - 단면형상: 수직; 수직 그리드 - 각도: 0 deg; 간격띄우기: 0 mm; 맞춤: 시작; 번호: 4; sets with these values: 2; 치수 - 길이: 4449.82 mm
기본 벽:WA111-철근콘크리트구조 벽 125mm_W3:5382087 | 지상 2층 | 429.8 | 4026.1 | 3120 | 새 구성 | 벽 | CW112-스테인리스 스틸 커튼월 | 7675291 | 커튼월 | 커튼월: CW112-스테인리스 스틸 커튼월 | 12.5614 | CW112-스테인리스 스틸 커튼월 | 2 | ID 데이터 - 마크: 15; 해설: AW; 구속조건 - 매스와 관련됨: no; 룸 경계: yes; 벽 베이스가 부착됩니다.: no; 상단이 부착됩니다.: no; 베이스 구속조건: 지상 2층; 상단 구속조건: 상위 레벨: 지상 3층; 미연결 높이: 3120 mm; 베이스 간격띄우기: 80 mm; 상단 간격띄우기: -1300 mm; 구조 - 구조: no; 구조적 용도: 비교좌장치; 단면형상 정의 - 단면형상: 수직; 수직 그리드 - 각도: 0 deg; 간격띄우기: 0 mm; 맞춤: 시작; 번호: 4; sets with these values: 2; 치수 - 길이: 4026.1 mm
기본 벽:WA111-철근콘크리트구조 벽 125mm_W3:5382087 | 지상 2층 | 429.8 | 4039.16 | 3120 | 새 구성 | 벽 | CW112-스테인리스 스틸 커튼월 | 7675291 | 커튼월 | 커튼월: CW112-스테인리스 스틸 커튼월 | 12.6022 | CW112-스테인리스 스틸 커튼월 | 2 | ID 데이터 - 마크: 16; 해설: AW; 구속조건 - 매스와 관련됨: no; 룸 경계: yes; 벽 베이스가 부착됩니다.: no; 상단이 부착됩니다.: no; 베이스 구속조건: 지상 2층; 상단 구속조건: 상위 레벨: 지상 3층; 미연결 높이: 3120 mm; 베이스 간격띄우기: 80 mm; 상단 간격띄우기: -1300 mm; 구조 - 구조: no; 구조적 용도: 비교좌장치; 단면형상 정의 - 단면형상: 수직; 수직 그리드 - 각도: 0 deg; 간격띄우기: 0 mm; 맞춤: 시작; 번호: 4; sets with these values: 2; 치수 - 길이: 4048.16 mm
기본 벽:WA111-철근콘크리트구조 벽 125mm_W3:5382097 | 지상 2층 | 429.8 | 3120 | 4907 | 새 구성 | 벽 | CW112-스테인리스 스틸 커튼월 | 7675291 | 커튼월 | 커튼월: CW112-스테인리스 스틸 커튼월 | 15.3098 | CW112-스테인리스 스틸 커튼월 | 2 | ID 데이터 - 마크: 17; 해설: AW; 구속조건 - 매스와 관련됨: no; 룸 경계: yes; 벽 베이스가 부착됩니다.: no; 상단이 부착됩니다.: no; 베이스 구속조건: 지상 2층; 상단 구속조건: 상위 레벨: 지상 3층; 미연결 높이: 3120 mm; 베이스 간격띄우기: 80 mm; 상단 간격띄우기: -1300 mm; 구조 - 구조: no; 구조적 용도: 비교좌장치; 단면형상 정의 - 단면형상: 수직; 수직 그리드 - 각도: 0 deg; 간격띄우기: 0 mm; 맞춤: 시작; 번호: 4; sets with these values: 2; 치수 - 길이: 4916 mm
기본 벽:WA111-철근콘크리트구조 벽 125mm_W3:5382097 | 지상 2층 | 429.8 | 3120 | 4907 | 새 구성 | 벽 | CW112-스테인리스 스틸 커튼월 | 7675291 | 커튼월 | 커튼월: CW112-스테인리스 스틸 커튼월 | 15.3098 | CW112-스테인리스 스틸 커튼월 | 2 | ID 데이터 - 마크: 18; 해설: AW; 구속조건 - 매스와 관련됨: no; 룸 경계: yes; 벽 베이스가 부착됩니다.: no; 상단이 부착됩니다.: no; 베이스 구속조건: 지상 2층; 상단 구속조건: 상위 레벨: 지상 3층; 미연결 높이: 3120 mm; 베이스 간격띄우기: 80 mm; 상단 간격띄우기: -1300 mm; 구조 - 구조: no; 구조적 용도: 비교좌장치; 단면형상 정의 - 단면형상: 수직; 수직 그리드 - 각도: 0 deg; 간격띄우기: 0 mm; 맞춤: 시작; 번호: 4; sets with these values: 2; 치수 - 길이: 4916 mm
기본 벽:WA111-철근콘크리트구조 벽 125mm_W3:5382111 | 지상 2층 | 429.8 | 6482 | 3120 | 새 구성 | 벽 | CW112-스테인리스 스틸 커튼월 | 7675291 | 커튼월 | 커튼월: CW112-스테인리스 스틸 커튼월 | 20.2238 | CW112-스테인리스 스틸 커튼월 | 2 | ID 데이터 - 마크: 19; 해설: AW; 구속조건 - 매스와 관련됨: no; 룸 경계: yes; 벽 베이스가 부착됩니다.: no; 상단이 부착됩니다.: no; 베이스 구속조건: 지상 2층; 상단 구속조건: 상위 레벨: 지상 3층; 미연결 높이: 3120 mm; 베이스 간격띄우기: 80 mm; 상단 간격띄우기: -1300 mm; 구조 - 구조: no; 구조적 용도: 비교좌장치; 단면형상 정의 - 단면형상: 수직; 수직 그리드 - 각도: 0 deg; 간격띄우기: 0 mm; 맞춤: 시작; 번호: 4; sets with these values: 2; 치수 - 길이: 6491 mm
기본 벽:WA111-철근콘크리트구조 벽 125mm_W3:5382125 | 지상 2층 | 429.8 | 8100 | 3120 | 새 구성 | 벽 | CW112-스테인리스 스틸 커튼월 | 7675291 | 커튼월 | 커튼월: CW112-스테인리스 스틸 커튼월 | 25.272 | CW112-스테인리스 스틸 커튼월 | 2 | ID 데이터 - 마크: 20; 해설: AW; 구속조건 - 매스와 관련됨: no; 룸 경계: yes; 벽 베이스가 부착됩니다.: no; 상단이 부착됩니다.: no; 베이스 구속조건: 지상 2층; 상단 구속조건: 상위 레벨: 지상 3층; 미연결 높이: 3120 mm; 베이스 간격띄우기: 80 mm; 상단 간격띄우기: -1300 mm; 구조 - 구조: no; 구조적 용도: 비교좌장치; 단면형상 정의 - 단면형상: 수직; 수직 그리드 - 각도: 0 deg; 간격띄우기: 0 mm; 맞춤: 시작; 번호: 4; sets with these values: 2; 치수 - 길이: 8100 mm
기본 벽:WA731-DRY WALL(C50, GS12.5mm) (1겹한면, GW50mm) 62.5mm:5382246 | 지상 2층 | 367.3 | 3020 | 2818.01 | 새 구성 | 벽 | CW112-스테인리스 스틸 커튼월 | 7675291 | 커튼월 | 커튼월: CW112-스테인리스 스틸 커튼월 | 8.51039 | CW112-스테인리스 스틸 커튼월 | 2 | ID 데이터 - 마크: 29; 해설: SSD; 구속조건 - 매스와 관련됨: no; 룸 경계: yes; 벽 베이스가 부착됩니다.: no; 상단이 부착됩니다.: no; 베이스 구속조건: 지상 2층; 상단 구속조건: 상위 레벨: 지상 3층; 미연결 높이: 3020 mm; 베이스 간격띄우기: 80 mm; 상단 간격띄우기: -1400 mm; 구조 - 구조: no; 구조적 용도: 비교좌장치; 단면형상 정의 - 단면형상: 수직; 수직 그리드 - 각도: 0 deg; 간격띄우기: 0 mm; 맞춤: 시작; 번호: 4; sets with these values: 2; 치수 - 길이: 2818.01 mm
기본 벽:WA211-시멘트벽돌(일반) 벽 (0.5B) 90mm:5382401 | 지상 2층 | 394.8 | 2818.01 | 3020 | 새 구성 | 벽 | CW112-스테인리스 스틸 커튼월 | 7675291 | 커튼월 | 커튼월: CW112-스테인리스 스틸 커튼월 | 8.51039 | CW112-스테인리스 스틸 커튼월 | 2 | ID 데이터 - 마크: 29; 해설: SSD; 구속조건 - 매스와 관련됨: no; 룸 경계: yes; 벽 베이스가 부착됩니다.: no; 상단이 부착됩니다.: no; 베이스 구속조건: 지상 2층; 상단 구속조건: 상위 레벨: 지상 3층; 미연결 높이: 3020 mm; 베이스 간격띄우기: 80 mm; 상단 간격띄우기: -1400 mm; 구조 - 구조: no; 구조적 용도: 비교좌장치; 단면형상 정의 - 단면형상: 수직; 수직 그리드 - 각도: 0 deg; 간격띄우기: 0 mm; 맞춤: 시작; 번호: 4; sets with these values: 2; 치수 - 길이: 2818.01 mm
기본 벽:WA211-시멘트벽돌(일반) 벽 (0.5B) 90mm:5382443 | 지상 2층 | 394.8 | 2720.98 | 3020 | 새 구성 | 벽 | CW112-스테인리스 스틸 커튼월 | 7675291 | 커튼월 | 커튼월: CW112-스테인리스 스틸 커튼월 | 8.21737 | CW112-스테인리스 스틸 커튼월 | 2 | ID 데이터 - 마크: 29; 해설: SSD; 구속조건 - 매스와 관련됨: no; 룸 경계: yes; 벽 베이스가 부착됩니다.: no; 상단이 부착됩니다.: no; 베이스 구속조건: 지상 2층; 상단 구속조건: 상위 레벨: 지상 3층; 미연결 높이: 3020 mm; 베이스 간격띄우기: 80 mm; 상단 간격띄우기: -1400 mm; 구조 - 구조: no; 구조적 용도: 비교좌장치; 단면형상 정의 - 단면형상: 수직; 수직 그리드 - 각도: 0 deg; 간격띄우기: 0 mm; 맞춤: 시작; 번호: 4; sets with these values: 2; 치수 - 길이: 2720.98 mm
기본 벽:WA731-DRY WALL(C50, GS12.5mm) (1겹한면, GW50mm) 62.5mm:5389060 | 지상 4층 | 367.3 |  |  | 새 구성 | 벽 | CW112-스테인리스 스틸 커튼월 | 7675291 | 커튼월 | 커튼월: CW112-스테인리스 스틸 커튼월 | 4.09252 | CW112-스테인리스 스틸 커튼월 | 2 | ID 데이터 - 마크: 29; 해설: SSD; 구속조건 - 매스와 관련됨: no; 룸 경계: yes; 벽 베이스가 부착됩니다.: no; 상단이 부착됩니다.: no; 베이스 구속조건: 지상 4층; 상단 구속조건: 상위 레벨: 지상 5층; 미연결 높이: 2620 mm; 베이스 간격띄우기: 80 mm; 상단 간격띄우기: -1400 mm; 구조 - 구조: no; 구조적 용도: 비교좌장치; 단면형상 정의 - 단면형상: 수직; 수직 그리드 - 각도: 0 deg; 간격띄우기: 0 mm; 맞춤: 시작; 번호: 4; sets with these values: 2; 치수 - 길이: 2750.01 mm; BaseQuantities - Area: 4.09252 m2
기본 벽:WA731-DRY WALL(C50, GS12.5mm) (1겹한면, GW50mm) 62.5mm:5389060 | 지상 4층 | 3048 | 2100 | 1500 | 새 구성 | 문 | DR121-쌍여닫이문(유리, 일반, 양개) 1500x2100mm | 7693130 | DR121-쌍여닫이문(철재, 일반, 양개) | DR121-쌍여닫이문(철재, 일반, 양개): DR121-쌍여닫이문(유리, 일반, 양개) 1500x2100mm | 3.7857 | DR121-쌍여닫이문(유리, 일반, 양개) 1500x2100mm | 2 | ID 데이터 - 마크: 25MMMMMM; 구속조건 - 레벨: 지상 4층; 씰 높이: 55 mm; 기타 - 헤드 높이: 2155 mm; 호스트 ID: 5355605; 치수 - 체적: 0.0603055 m3; 데이터 - 벽체 opening 면적: 3.15 m2
기본 벽:WA731-DRY WALL(C50, GS12.5mm) (1겹한면, GW50mm) 62.5mm:5389062 | 지상 5층 | 367.3 |  |  | 새 구성 | 벽 | CW112-스테인리스 스틸 커튼월 | 7675291 | 커튼월 | 커튼월: CW112-스테인리스 스틸 커튼월 | 4.2235 | CW112-스테인리스 스틸 커튼월 | 2 | ID 데이터 - 마크: 29; 해설: SSD; 구속조건 - 매스와 관련됨: no; 룸 경계: yes; 벽 베이스가 부착됩니다.: no; 상단이 부착됩니다.: no; 베이스 구속조건: 지상 5층; 상단 구속조건: 상위 레벨: 지상 6층; 미연결 높이: 2620 mm; 베이스 간격띄우기: 80 mm; 상단 간격띄우기: -1400 mm; 구조 - 구조: no; 구조적 용도: 비교좌장치; 단면형상 정의 - 단면형상: 수직; 수직 그리드 - 각도: 0 deg; 간격띄우기: 0 mm; 맞춤: 시작; 번호: 4; sets with these values: 2; 치수 - 길이: 2800 mm; BaseQuantities - Area: 4.2235 m2
기본 벽:WA731-DRY WALL(C50, GS12.5mm) (1겹한면, GW50mm) 62.5mm:5389062 | 지상 5층 | 3048 | 2100 | 1500 | 새 구성 | 문 | DR121-쌍여닫이문(유리, 일반, 양개) 1500x2100mm | 7693130 | DR121-쌍여닫이문(철재, 일반, 양개) | DR121-쌍여닫이문(철재, 일반, 양개): DR121-쌍여닫이문(유리, 일반, 양개) 1500x2100mm | 3.7857 | DR121-쌍여닫이문(유리, 일반, 양개) 1500x2100mm | 2 | ID 데이터 - 마크: 25MMMM; 구속조건 - 레벨: 지상 5층; 씰 높이: 55 mm; 기타 - 헤드 높이: 2155 mm; 호스트 ID: 5355823; 치수 - 체적: 0.0603055 m3; 데이터 - 벽체 opening 면적: 3.15 m2
기본 벽:WA211-시멘트벽돌(일반) 벽 (0.5B) 90mm:5389253 | 지상 6층 | 394.8 |  |  | 새 구성 | 벽 | CW112-스테인리스 스틸 커튼월 | 7675291 | 커튼월 | 커튼월: CW112-스테인리스 스틸 커튼월 | 4.2104 | CW112-스테인리스 스틸 커튼월 | 2 | ID 데이터 - 마크: 29; 해설: SSD; 구속조건 - 매스와 관련됨: no; 룸 경계: yes; 벽 베이스가 부착됩니다.: no; 상단이 부착됩니다.: no; 베이스 구속조건: 지상 6층; 상단 구속조건: 상위 레벨: 지상 7층; 미연결 높이: 2620 mm; 베이스 간격띄우기: 80 mm; 상단 간격띄우기: -1400 mm; 구조 - 구조: no; 구조적 용도: 비교좌장치; 단면형상 정의 - 단면형상: 수직; 수직 그리드 - 각도: 0 deg; 간격띄우기: 0 mm; 맞춤: 시작; 번호: 4; sets with these values: 2; 치수 - 길이: 2795 mm; BaseQuantities - Area: 4.2104 m2
기본 벽:WA211-시멘트벽돌(일반) 벽 (0.5B) 90mm:5389253 | 지상 6층 | 3048 | 1500 | 2100 | 새 구성 | 문 | DR121-쌍여닫이문(유리, 일반, 양개) 1500x2100mm | 7693130 | DR121-쌍여닫이문(철재, 일반, 양개) | DR121-쌍여닫이문(철재, 일반, 양개): DR121-쌍여닫이문(유리, 일반, 양개) 1500x2100mm | 3.7857 | DR121-쌍여닫이문(유리, 일반, 양개) 1500x2100mm | 2 | ID 데이터 - 마크: 25NNNN; 구속조건 - 레벨: 지상 6층; 씰 높이: 55 mm; 기타 - 헤드 높이: 2155 mm; 호스트 ID: 5356041; 치수 - 체적: 0.0603055 m3; 데이터 - 벽체 opening 면적: 3.15 m2
기본 벽:WA211-시멘트벽돌(일반) 벽 (0.5B) 90mm:5389313 | 지상 7층 | 394.8 |  |  | 새 구성 | 벽 | CW112-스테인리스 스틸 커튼월 | 7675291 | 커튼월 | 커튼월: CW112-스테인리스 스틸 커튼월 | 4.2104 | CW112-스테인리스 스틸 커튼월 | 2 | ID 데이터 - 마크: 29; 해설: SSD; 구속조건 - 매스와 관련됨: no; 룸 경계: yes; 벽 베이스가 부착됩니다.: no; 상단이 부착됩니다.: no; 베이스 구속조건: 지상 7층; 상단 구속조건: 상위 레벨: 지상 8층; 미연결 높이: 2620 mm; 베이스 간격띄우기: 80 mm; 상단 간격띄우기: -1400 mm; 구조 - 구조: no; 구조적 용도: 비교좌장치; 단면형상 정의 - 단면형상: 수직; 수직 그리드 - 각도: 0 deg; 간격띄우기: 0 mm; 맞춤: 시작; 번호: 4; sets with these values: 2; 치수 - 길이: 2795 mm; BaseQuantities - Area: 4.2104 m2
기본 벽:WA211-시멘트벽돌(일반) 벽 (0.5B) 90mm:5389313 | 지상 7층 | 3048 | 1500 | 2100 | 새 구성 | 문 | DR121-쌍여닫이문(유리, 일반, 양개) 1500x2100mm | 7693130 | DR121-쌍여닫이문(철재, 일반, 양개) | DR121-쌍여닫이문(철재, 일반, 양개): DR121-쌍여닫이문(유리, 일반, 양개) 1500x2100mm | 3.7857 | DR121-쌍여닫이문(유리, 일반, 양개) 1500x2100mm | 2 | ID 데이터 - 마크: 25OOOO; 구속조건 - 레벨: 지상 7층; 씰 높이: 55 mm; 기타 - 헤드 높이: 2155 mm; 호스트 ID: 5356259; 치수 - 체적: 0.0603055 m3; 데이터 - 벽체 opening 면적: 3.15 m2
기본 벽:WA211-시멘트벽돌(일반) 벽 (0.5B) 90mm:5389373 | 지상 8층 | 394.8 |  |  | 새 구성 | 벽 | CW112-스테인리스 스틸 커튼월 | 7675291 | 커튼월 | 커튼월: CW112-스테인리스 스틸 커튼월 | 4.2104 | CW112-스테인리스 스틸 커튼월 | 2 | ID 데이터 - 마크: 29; 해설: SSD; 구속조건 - 매스와 관련됨: no; 룸 경계: yes; 벽 베이스가 부착됩니다.: no; 상단이 부착됩니다.: no; 베이스 구속조건: 지상 8층; 상단 구속조건: 상위 레벨: 지상 9층; 미연결 높이: 2620 mm; 베이스 간격띄우기: 80 mm; 상단 간격띄우기: -1400 mm; 구조 - 구조: no; 구조적 용도: 비교좌장치; 단면형상 정의 - 단면형상: 수직; 수직 그리드 - 각도: 0 deg; 간격띄우기: 0 mm; 맞춤: 시작; 번호: 4; sets with these values: 2; 치수 - 길이: 2795 mm; BaseQuantities - Area: 4.2104 m2
기본 벽:WA211-시멘트벽돌(일반) 벽 (0.5B) 90mm:5389373 | 지상 8층 | 3048 | 1500 | 2100 | 새 구성 | 문 | DR121-쌍여닫이문(유리, 일반, 양개) 1500x2100mm | 7693130 | DR121-쌍여닫이문(철재, 일반, 양개) | DR121-쌍여닫이문(철재, 일반, 양개): DR121-쌍여닫이문(유리, 일반, 양개) 1500x2100mm | 3.7857 | DR121-쌍여닫이문(유리, 일반, 양개) 1500x2100mm | 2 | ID 데이터 - 마크: 25PPPP; 구속조건 - 레벨: 지상 8층; 씰 높이: 55 mm; 기타 - 헤드 높이: 2155 mm; 호스트 ID: 5356477; 치수 - 체적: 0.0603055 m3; 데이터 - 벽체 opening 면적: 3.15 m2
기본 벽:WA211-시멘트벽돌(일반) 벽 (0.5B) 90mm:5393897 | 지상 9층 | 394.8 |  |  | 새 구성 | 벽 | CW112-스테인리스 스틸 커튼월 | 7675291 | 커튼월 | 커튼월: CW112-스테인리스 스틸 커튼월 | 16.5176 | CW112-스테인리스 스틸 커튼월 | 2 | ID 데이터 - 마크: 27; 해설: SSD; 구속조건 - 매스와 관련됨: no; 룸 경계: yes; 벽 베이스가 부착됩니다.: no; 상단이 부착됩니다.: no; 베이스 구속조건: 지상 9층; 상단 구속조건: 상위 레벨: 지상 10층; 미연결 높이: 3020 mm; 베이스 간격띄우기: 80 mm; 상단 간격띄우기: -1400 mm; 구조 - 구조: no; 구조적 용도: 비교좌장치; 단면형상 정의 - 단면형상: 수직; 수직 그리드 - 각도: 0 deg; 간격띄우기: 0 mm; 맞춤: 시작; 번호: 4; sets with these values: 2; 치수 - 길이: 6500.03 mm; BaseQuantities - Area: 16.5176 m2
기본 벽:WA211-시멘트벽돌(일반) 벽 (0.5B) 90mm:5397596 | 지상 4층 | 394.8 |  |  | 새 구성 | 벽 | CW112-스테인리스 스틸 커튼월 | 7675291 | 커튼월 | 커튼월: CW112-스테인리스 스틸 커튼월 | 13.9175 | CW112-스테인리스 스틸 커튼월 | 2 | ID 데이터 - 마크: 27; 해설: SSD; 구속조건 - 매스와 관련됨: no; 룸 경계: yes; 벽 베이스가 부착됩니다.: no; 상단이 부착됩니다.: no; 베이스 구속조건: 지상 4층; 상단 구속조건: 상위 레벨: 지상 5층; 미연결 높이: 2620 mm; 베이스 간격띄우기: 80 mm; 상단 간격띄우기: -1400 mm; 구조 - 구조: no; 구조적 용도: 비교좌장치; 단면형상 정의 - 단면형상: 수직; 수직 그리드 - 각도: 0 deg; 간격띄우기: 0 mm; 맞춤: 시작; 번호: 4; sets with these values: 2; 치수 - 길이: 6500 mm; BaseQuantities - Area: 13.9175 m2
기본 벽:WA211-시멘트벽돌(일반) 벽 (0.5B) 90mm:5397623 | 지상 5층 | 394.8 |  |  | 새 구성 | 벽 | CW112-스테인리스 스틸 커튼월 | 7675291 | 커튼월 | 커튼월: CW112-스테인리스 스틸 커튼월 | 13.9175 | CW112-스테인리스 스틸 커튼월 | 2 | ID 데이터 - 마크: 27; 해설: SSD; 구속조건 - 매스와 관련됨: no; 룸 경계: yes; 벽 베이스가 부착됩니다.: no; 상단이 부착됩니다.: no; 베이스 구속조건: 지상 5층; 상단 구속조건: 상위 레벨: 지상 6층; 미연결 높이: 2620 mm; 베이스 간격띄우기: 80 mm; 상단 간격띄우기: -1400 mm; 구조 - 구조: no; 구조적 용도: 비교좌장치; 단면형상 정의 - 단면형상: 수직; 수직 그리드 - 각도: 0 deg; 간격띄우기: 0 mm; 맞춤: 시작; 번호: 4; sets with these values: 2; 치수 - 길이: 6500 mm; BaseQuantities - Area: 13.9175 m2
기본 벽:WA211-시멘트벽돌(일반) 벽 (0.5B) 90mm:5397650 | 지상 6층 | 394.8 |  |  | 새 구성 | 벽 | CW112-스테인리스 스틸 커튼월 | 7675291 | 커튼월 | 커튼월: CW112-스테인리스 스틸 커튼월 | 13.9175 | CW112-스테인리스 스틸 커튼월 | 2 | ID 데이터 - 마크: 27; 해설: SSD; 구속조건 - 매스와 관련됨: no; 룸 경계: yes; 벽 베이스가 부착됩니다.: no; 상단이 부착됩니다.: no; 베이스 구속조건: 지상 6층; 상단 구속조건: 상위 레벨: 지상 7층; 미연결 높이: 2620 mm; 베이스 간격띄우기: 80 mm; 상단 간격띄우기: -1400 mm; 구조 - 구조: no; 구조적 용도: 비교좌장치; 단면형상 정의 - 단면형상: 수직; 수직 그리드 - 각도: 0 deg; 간격띄우기: 0 mm; 맞춤: 시작; 번호: 4; sets with these values: 2; 치수 - 길이: 6500 mm; BaseQuantities - Area: 13.9175 m2
기본 벽:WA211-시멘트벽돌(일반) 벽 (0.5B) 90mm:5397677 | 지상 7층 | 394.8 |  |  | 새 구성 | 벽 | CW112-스테인리스 스틸 커튼월 | 7675291 | 커튼월 | 커튼월: CW112-스테인리스 스틸 커튼월 | 13.9043 | CW112-스테인리스 스틸 커튼월 | 2 | ID 데이터 - 마크: 27; 해설: SSD; 구속조건 - 매스와 관련됨: no; 룸 경계: yes; 벽 베이스가 부착됩니다.: no; 상단이 부착됩니다.: no; 베이스 구속조건: 지상 7층; 상단 구속조건: 상위 레벨: 지상 8층; 미연결 높이: 2620 mm; 베이스 간격띄우기: 80 mm; 상단 간격띄우기: -1400 mm; 구조 - 구조: no; 구조적 용도: 비교좌장치; 단면형상 정의 - 단면형상: 수직; 수직 그리드 - 각도: 0 deg; 간격띄우기: 0 mm; 맞춤: 시작; 번호: 4; sets with these values: 2; 치수 - 길이: 6494.97 mm; BaseQuantities - Area: 13.9043 m2
기본 벽:WA211-시멘트벽돌(일반) 벽 (0.5B) 90mm:5397704 | 지상 8층 | 394.8 |  |  | 새 구성 | 벽 | CW112-스테인리스 스틸 커튼월 | 7675291 | 커튼월 | 커튼월: CW112-스테인리스 스틸 커튼월 | 13.9174 | CW112-스테인리스 스틸 커튼월 | 2 | ID 데이터 - 마크: 27; 해설: SSD; 구속조건 - 매스와 관련됨: no; 룸 경계: yes; 벽 베이스가 부착됩니다.: no; 상단이 부착됩니다.: no; 베이스 구속조건: 지상 8층; 상단 구속조건: 상위 레벨: 지상 9층; 미연결 높이: 2620 mm; 베이스 간격띄우기: 80 mm; 상단 간격띄우기: -1400 mm; 구조 - 구조: no; 구조적 용도: 비교좌장치; 단면형상 정의 - 단면형상: 수직; 수직 그리드 - 각도: 0 deg; 간격띄우기: 0 mm; 맞춤: 시작; 번호: 4; sets with these values: 2; 치수 - 길이: 6499.97 mm; BaseQuantities - Area: 13.9174 m2
기본 벽:WA731-DRY WALL(C50, GS12.5mm) (1겹한면, GW50mm) 62.5mm:5406055 | 지상 3층 | 367.3 | 2620 | 2850 | 새 구성 | 벽 | CW112-스테인리스 스틸 커튼월 | 7675291 | 커튼월 | 커튼월: CW112-스테인리스 스틸 커튼월 | 7.467 | CW112-스테인리스 스틸 커튼월 | 2 | ID 데이터 - 해설: SSD; 구속조건 - 매스와 관련됨: no; 룸 경계: yes; 벽 베이스가 부착됩니다.: no; 상단이 부착됩니다.: no; 베이스 구속조건: 지상 3층; 상단 구속조건: 상위 레벨: 지상 4층; 미연결 높이: 2620 mm; 베이스 간격띄우기: 80 mm; 상단 간격띄우기: -1400 mm; 구조 - 구조: no; 구조적 용도: 비교좌장치; 단면형상 정의 - 단면형상: 수직; 수직 그리드 - 각도: 0 deg; 간격띄우기: 0 mm; 맞춤: 시작; 번호: 4; sets with these values: 2; 치수 - 길이: 2850 mm
기본 벽:WA111-철근콘크리트구조 벽 125mm_W3:5431504 | 지상 1층 | 429.8 | 7200.02 | 3520 | 새 구성 | 벽 | CW112-스테인리스 스틸 커튼월 | 7675291 | 커튼월 | 커튼월: CW112-스테인리스 스틸 커튼월 | 25.3441 | CW112-스테인리스 스틸 커튼월 | 2 | ID 데이터 - 마크: 2; 해설: SSD; 구속조건 - 매스와 관련됨: no; 룸 경계: yes; 벽 베이스가 부착됩니다.: no; 상단이 부착됩니다.: no; 베이스 구속조건: 지상 1층; 상단 구속조건: 상위 레벨: 지상 2층; 미연결 높이: 3520 mm; 베이스 간격띄우기: 80 mm; 상단 간격띄우기: -1200 mm; 구조 - 구조: no; 구조적 용도: 비교좌장치; 단면형상 정의 - 단면형상: 수직; 수직 그리드 - 각도: 0 deg; 간격띄우기: 0 mm; 맞춤: 시작; 번호: 4; sets with these values: 2; 치수 - 길이: 7200.02 mm
기본 벽:WA111-철근콘크리트구조 벽 125mm_W3:5431681 | 지상 1층 | 429.8 | 6600 | 3520 | 새 구성 | 벽 | CW112-스테인리스 스틸 커튼월 | 7675291 | 커튼월 | 커튼월: CW112-스테인리스 스틸 커튼월 | 23.232 | CW112-스테인리스 스틸 커튼월 | 2 | ID 데이터 - 마크: 3; 해설: SSD; 구속조건 - 매스와 관련됨: no; 룸 경계: yes; 벽 베이스가 부착됩니다.: no; 상단이 부착됩니다.: no; 베이스 구속조건: 지상 1층; 상단 구속조건: 상위 레벨: 지상 2층; 미연결 높이: 3520 mm; 베이스 간격띄우기: 80 mm; 상단 간격띄우기: -1200 mm; 구조 - 구조: no; 구조적 용도: 비교좌장치; 단면형상 정의 - 단면형상: 수직; 수직 그리드 - 각도: 0 deg; 간격띄우기: 0 mm; 맞춤: 시작; 번호: 4; sets with these values: 2; 치수 - 길이: 6600 mm
기본 벽:WA111-철근콘크리트구조 벽 125mm_W3:5432100 | 지상 1층 | 429.8 | 10900 | 3520 | 새 구성 | 벽 | CW112-스테인리스 스틸 커튼월 | 7675291 | 커튼월 | 커튼월: CW112-스테인리스 스틸 커튼월 | 38.3679 | CW112-스테인리스 스틸 커튼월 | 2 | ID 데이터 - 마크: 5; 해설: SSD; 구속조건 - 매스와 관련됨: no; 룸 경계: yes; 벽 베이스가 부착됩니다.: no; 상단이 부착됩니다.: no; 베이스 구속조건: 지상 1층; 상단 구속조건: 상위 레벨: 지상 2층; 미연결 높이: 3520 mm; 베이스 간격띄우기: 80 mm; 상단 간격띄우기: -1200 mm; 구조 - 구조: no; 구조적 용도: 비교좌장치; 단면형상 정의 - 단면형상: 수직; 수직 그리드 - 각도: 0 deg; 간격띄우기: 0 mm; 맞춤: 시작; 번호: 4; sets with these values: 2; 치수 - 길이: 10900 mm
기본 벽:WA111-철근콘크리트구조 벽 125mm_W3:5432236 | 지상 1층 | 429.8 | 11900 | 3520 | 새 구성 | 벽 | CW112-스테인리스 스틸 커튼월 | 7675291 | 커튼월 | 커튼월: CW112-스테인리스 스틸 커튼월 | 41.888 | CW112-스테인리스 스틸 커튼월 | 2 | ID 데이터 - 마크: 6; 해설: SSD; 구속조건 - 매스와 관련됨: no; 룸 경계: yes; 벽 베이스가 부착됩니다.: no; 상단이 부착됩니다.: no; 베이스 구속조건: 지상 1층; 상단 구속조건: 상위 레벨: 지상 2층; 미연결 높이: 3520 mm; 베이스 간격띄우기: 80 mm; 상단 간격띄우기: -1200 mm; 구조 - 구조: no; 구조적 용도: 비교좌장치; 단면형상 정의 - 단면형상: 수직; 수직 그리드 - 각도: 0 deg; 간격띄우기: 0 mm; 맞춤: 시작; 번호: 4; sets with these values: 2; 치수 - 길이: 11900 mm
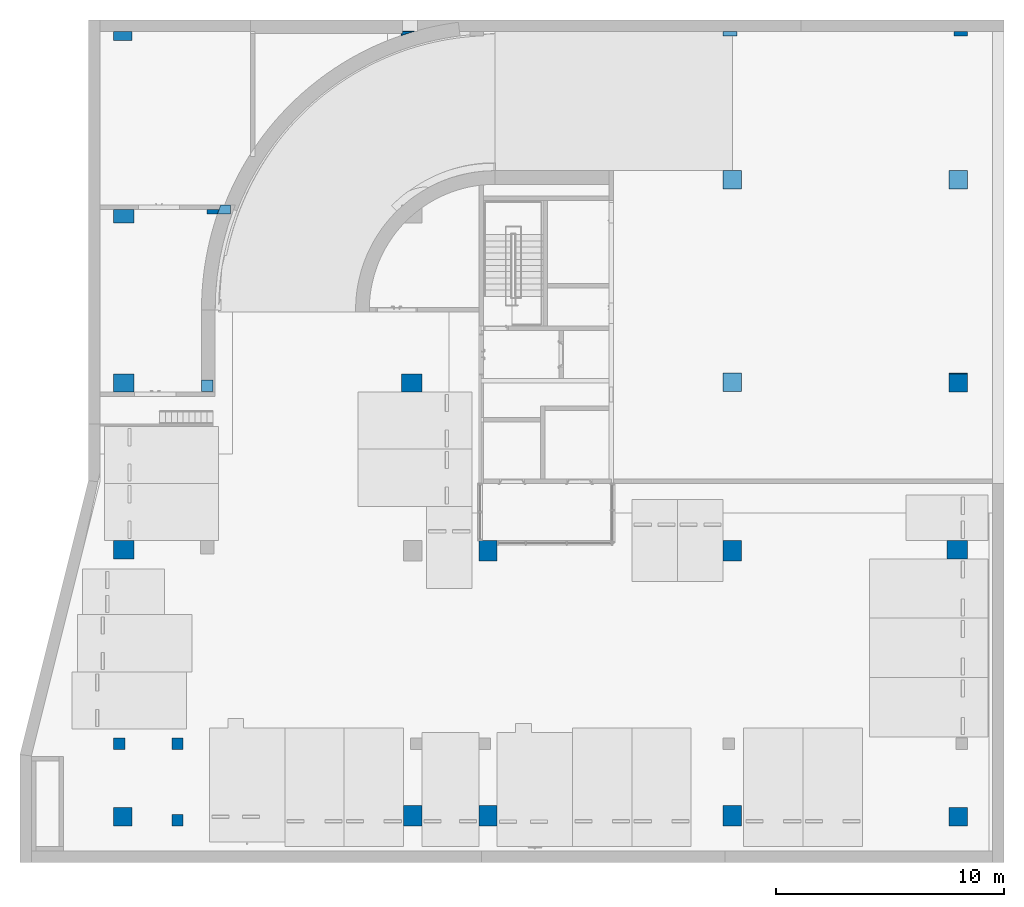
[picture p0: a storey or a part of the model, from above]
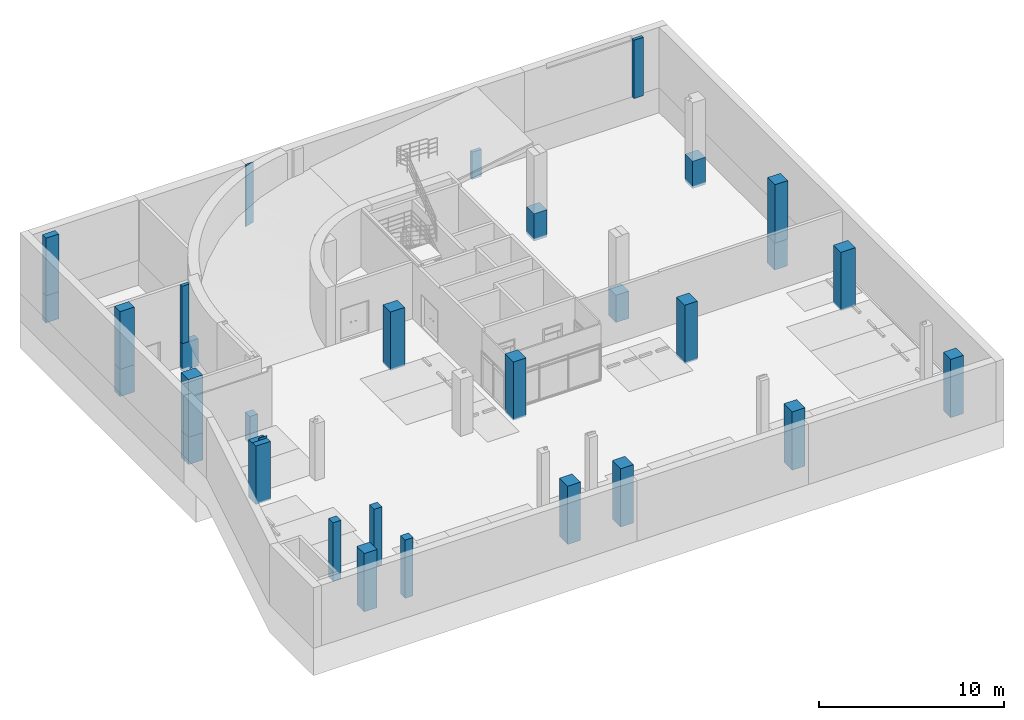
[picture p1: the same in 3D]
Properties of the parts of a building model (IFC2X3), part 26 of 39

# IfcOpeningElement: Opening (863)
Name | In | Depth (mm) | Height (mm) | Width (mm) | 생성 공정 | 카테고리 | 유형 | 유형 ID | 패밀리 | 패밀리 및 유형 | 면적 (m2) | Reference | Pset_OpeningElementCommon, sets with these values
기본 벽:WA111-철근콘크리트구조 벽 125mm_W3:5432344 | 지상 1층 | 429.8 | 9900 | 3520 | 새 구성 | 벽 | CW112-스테인리스 스틸 커튼월 | 7675291 | 커튼월 | 커튼월: CW112-스테인리스 스틸 커튼월 | 34.848 | CW112-스테인리스 스틸 커튼월 | 2 | ID 데이터 - 마크: 8; 해설: SSD; 구속조건 - 매스와 관련됨: no; 룸 경계: yes; 벽 베이스가 부착됩니다.: no; 상단이 부착됩니다.: no; 베이스 구속조건: 지상 1층; 상단 구속조건: 상위 레벨: 지상 2층; 미연결 높이: 3520 mm; 베이스 간격띄우기: 80 mm; 상단 간격띄우기: -1200 mm; 구조 - 구조: no; 구조적 용도: 비교좌장치; 단면형상 정의 - 단면형상: 수직; 수직 그리드 - 각도: 0 deg; 간격띄우기: 0 mm; 맞춤: 시작; 번호: 4; sets with these values: 2; 치수 - 길이: 9900 mm
기본 벽:WA111-철근콘크리트구조 벽 125mm_W3:5432344 | 지상 1층 | 429.8 | 11900 | 3520 | 새 구성 | 벽 | CW112-스테인리스 스틸 커튼월 | 7675291 | 커튼월 | 커튼월: CW112-스테인리스 스틸 커튼월 | 41.888 | CW112-스테인리스 스틸 커튼월 | 2 | ID 데이터 - 마크: 6; 해설: SSD; 구속조건 - 매스와 관련됨: no; 룸 경계: yes; 벽 베이스가 부착됩니다.: no; 상단이 부착됩니다.: no; 베이스 구속조건: 지상 1층; 상단 구속조건: 상위 레벨: 지상 2층; 미연결 높이: 3520 mm; 베이스 간격띄우기: 80 mm; 상단 간격띄우기: -1200 mm; 구조 - 구조: no; 구조적 용도: 비교좌장치; 단면형상 정의 - 단면형상: 수직; 수직 그리드 - 각도: 0 deg; 간격띄우기: 0 mm; 맞춤: 시작; 번호: 4; sets with these values: 2; 치수 - 길이: 11900 mm
기본 벽:WA111-철근콘크리트구조 벽 125mm_W3:5432344 | 지상 1층 | 429.8 | 9082 | 3520 | 새 구성 | 벽 | CW112-스테인리스 스틸 커튼월 | 7675291 | 커튼월 | 커튼월: CW112-스테인리스 스틸 커튼월 | 31.9686 | CW112-스테인리스 스틸 커튼월 | 2 | ID 데이터 - 마크: 9; 해설: SSD; 구속조건 - 매스와 관련됨: no; 룸 경계: yes; 벽 베이스가 부착됩니다.: no; 상단이 부착됩니다.: no; 베이스 구속조건: 지상 1층; 상단 구속조건: 상위 레벨: 지상 2층; 미연결 높이: 3520 mm; 베이스 간격띄우기: 80 mm; 상단 간격띄우기: -1200 mm; 구조 - 구조: no; 구조적 용도: 비교좌장치; 단면형상 정의 - 단면형상: 수직; 수직 그리드 - 각도: 0 deg; 간격띄우기: 0 mm; 맞춤: 시작; 번호: 4; sets with these values: 2; 치수 - 길이: 9082 mm
기본 벽:WA111-철근콘크리트구조 벽 125mm_W3:5432458 | 지상 1층 | 429.8 | 9082 | 3520 | 새 구성 | 벽 | CW112-스테인리스 스틸 커튼월 | 7675291 | 커튼월 | 커튼월: CW112-스테인리스 스틸 커튼월 | 31.9686 | CW112-스테인리스 스틸 커튼월 | 2 | ID 데이터 - 마크: 9; 해설: SSD; 구속조건 - 매스와 관련됨: no; 룸 경계: yes; 벽 베이스가 부착됩니다.: no; 상단이 부착됩니다.: no; 베이스 구속조건: 지상 1층; 상단 구속조건: 상위 레벨: 지상 2층; 미연결 높이: 3520 mm; 베이스 간격띄우기: 80 mm; 상단 간격띄우기: -1200 mm; 구조 - 구조: no; 구조적 용도: 비교좌장치; 단면형상 정의 - 단면형상: 수직; 수직 그리드 - 각도: 0 deg; 간격띄우기: 0 mm; 맞춤: 시작; 번호: 4; sets with these values: 2; 치수 - 길이: 9082 mm
기본 벽:WA111-철근콘크리트구조 벽 125mm_W3:5432458 | 지상 1층 | 429.8 | 11900 | 3520 | 새 구성 | 벽 | CW112-스테인리스 스틸 커튼월 | 7675291 | 커튼월 | 커튼월: CW112-스테인리스 스틸 커튼월 | 41.888 | CW112-스테인리스 스틸 커튼월 | 2 | ID 데이터 - 마크: 6; 해설: SSD; 구속조건 - 매스와 관련됨: no; 룸 경계: yes; 벽 베이스가 부착됩니다.: no; 상단이 부착됩니다.: no; 베이스 구속조건: 지상 1층; 상단 구속조건: 상위 레벨: 지상 2층; 미연결 높이: 3520 mm; 베이스 간격띄우기: 80 mm; 상단 간격띄우기: -1200 mm; 구조 - 구조: no; 구조적 용도: 비교좌장치; 단면형상 정의 - 단면형상: 수직; 수직 그리드 - 각도: 0 deg; 간격띄우기: 0 mm; 맞춤: 시작; 번호: 4; sets with these values: 2; 치수 - 길이: 11900 mm
기본 벽:WA111-철근콘크리트구조 벽 125mm_W3:5432458 | 지상 1층 | 429.8 | 9900 | 3520 | 새 구성 | 벽 | CW112-스테인리스 스틸 커튼월 | 7675291 | 커튼월 | 커튼월: CW112-스테인리스 스틸 커튼월 | 34.848 | CW112-스테인리스 스틸 커튼월 | 2 | ID 데이터 - 마크: 8; 해설: SSD; 구속조건 - 매스와 관련됨: no; 룸 경계: yes; 벽 베이스가 부착됩니다.: no; 상단이 부착됩니다.: no; 베이스 구속조건: 지상 1층; 상단 구속조건: 상위 레벨: 지상 2층; 미연결 높이: 3520 mm; 베이스 간격띄우기: 80 mm; 상단 간격띄우기: -1200 mm; 구조 - 구조: no; 구조적 용도: 비교좌장치; 단면형상 정의 - 단면형상: 수직; 수직 그리드 - 각도: 0 deg; 간격띄우기: 0 mm; 맞춤: 시작; 번호: 4; sets with these values: 2; 치수 - 길이: 9900 mm
기본 벽:WA111-철근콘크리트구조 벽 125mm_W3:5432560 | 지상 1층 | 429.8 | 10900 | 3520 | 새 구성 | 벽 | CW112-스테인리스 스틸 커튼월 | 7675291 | 커튼월 | 커튼월: CW112-스테인리스 스틸 커튼월 | 38.3681 | CW112-스테인리스 스틸 커튼월 | 2 | ID 데이터 - 마크: 10; 해설: SSD; 구속조건 - 매스와 관련됨: no; 룸 경계: yes; 벽 베이스가 부착됩니다.: no; 상단이 부착됩니다.: no; 베이스 구속조건: 지상 1층; 상단 구속조건: 상위 레벨: 지상 2층; 미연결 높이: 3520 mm; 베이스 간격띄우기: 80 mm; 상단 간격띄우기: -1200 mm; 구조 - 구조: no; 구조적 용도: 비교좌장치; 단면형상 정의 - 단면형상: 수직; 수직 그리드 - 각도: 0 deg; 간격띄우기: 0 mm; 맞춤: 시작; 번호: 4; sets with these values: 2; 치수 - 길이: 10900 mm
기본 벽:WA111-철근콘크리트구조 벽 125mm_W3:5432926 | 지상 1층 | 429.8 | 5020 | 7982 | 새 구성 | 벽 | CW112-스테인리스 스틸 커튼월 | 7675291 | 커튼월 | 커튼월: CW112-스테인리스 스틸 커튼월 | 40.0696 | CW112-스테인리스 스틸 커튼월 | 2 | ID 데이터 - 마크: 12; 해설: SSD; 구속조건 - 매스와 관련됨: no; 룸 경계: yes; 벽 베이스가 부착됩니다.: no; 상단이 부착됩니다.: no; 베이스 구속조건: 지상 1층; 상단 구속조건: 상위 레벨: 지상 2층; 미연결 높이: 5020 mm; 베이스 간격띄우기: -1420 mm; 상단 간격띄우기: -1200 mm; 구조 - 구조: no; 구조적 용도: 비교좌장치; 단면형상 정의 - 단면형상: 수직; 수직 그리드 - 각도: 0 deg; 간격띄우기: 0 mm; 맞춤: 시작; 번호: 4; sets with these values: 2; 치수 - 길이: 7982 mm
기본 벽:WA111-철근콘크리트구조 벽 125mm_W3:5433044 | 지상 1층 | 429.8 | 4020 | 6540 | 새 구성 | 벽 | CW112-스테인리스 스틸 커튼월 | 7675291 | 커튼월 | 커튼월: CW112-스테인리스 스틸 커튼월 | 26.2908 | CW112-스테인리스 스틸 커튼월 | 2 | ID 데이터 - 마크: 11; 해설: SSD; 구속조건 - 매스와 관련됨: no; 룸 경계: yes; 벽 베이스가 부착됩니다.: no; 상단이 부착됩니다.: no; 베이스 구속조건: 지상 1층; 상단 구속조건: 상위 레벨: 지상 2층; 미연결 높이: 4020 mm; 베이스 간격띄우기: -420 mm; 상단 간격띄우기: -1200 mm; 구조 - 구조: no; 구조적 용도: 비교좌장치; 단면형상 정의 - 단면형상: 수직; 수직 그리드 - 각도: 0 deg; 간격띄우기: 0 mm; 맞춤: 시작; 번호: 4; sets with these values: 2; 치수 - 길이: 6540 mm
기본 벽:WA211-시멘트벽돌(일반) 벽 (0.5B) 90mm:5476646 | 지상 1층 | 394.8 | 9900 | 3520 | 새 구성 | 벽 | CW112-스테인리스 스틸 커튼월 | 7675291 | 커튼월 | 커튼월: CW112-스테인리스 스틸 커튼월 | 34.848 | CW112-스테인리스 스틸 커튼월 | 2 | ID 데이터 - 마크: 22; 해설: SSD; 구속조건 - 매스와 관련됨: no; 룸 경계: yes; 벽 베이스가 부착됩니다.: no; 상단이 부착됩니다.: no; 베이스 구속조건: 지상 1층; 상단 구속조건: 상위 레벨: 지상 2층; 미연결 높이: 3520 mm; 베이스 간격띄우기: 80 mm; 상단 간격띄우기: -1200 mm; 구조 - 구조: no; 구조적 용도: 비교좌장치; 단면형상 정의 - 단면형상: 수직; 수직 그리드 - 각도: 0 deg; 간격띄우기: 0 mm; 맞춤: 시작; 번호: 4; sets with these values: 2; 치수 - 길이: 9900 mm
기본 벽:WA211-시멘트벽돌(일반) 벽 (0.5B) 90mm:5476646 | 지상 1층 | 394.8 | 3520 | 9000 | 새 구성 | 벽 | CW112-스테인리스 스틸 커튼월 | 7675291 | 커튼월 | 커튼월: CW112-스테인리스 스틸 커튼월 | 31.68 | CW112-스테인리스 스틸 커튼월 | 2 | ID 데이터 - 마크: 18; 해설: SSD; 구속조건 - 매스와 관련됨: no; 룸 경계: yes; 벽 베이스가 부착됩니다.: no; 상단이 부착됩니다.: no; 베이스 구속조건: 지상 1층; 상단 구속조건: 상위 레벨: 지상 2층; 미연결 높이: 3520 mm; 베이스 간격띄우기: 80 mm; 상단 간격띄우기: -1200 mm; 구조 - 구조: no; 구조적 용도: 비교좌장치; 단면형상 정의 - 단면형상: 수직; 수직 그리드 - 각도: 0 deg; 간격띄우기: 0 mm; 맞춤: 시작; 번호: 4; sets with these values: 2; 치수 - 길이: 9000 mm
기본 벽:A2-22-02A-압출스티로폼, BRACKET(STEEL), ALC블록 (150mm):5897661 | 지상 4층 | 454.8 | 2100 | 15382 | 새 구성 | 벽 | CW112-스테인리스 스틸 커튼월 | 7675291 | 커튼월 | 커튼월: CW112-스테인리스 스틸 커튼월 | 32.3022 | CW112-스테인리스 스틸 커튼월 | 2 | ID 데이터 - 마크: 25; 해설: AW; 구속조건 - 매스와 관련됨: no; 룸 경계: yes; 벽 베이스가 부착됩니다.: no; 상단이 부착됩니다.: no; 베이스 구속조건: 지상 4층; 상단 구속조건: 상위 레벨: 지상 5층; 미연결 높이: 2100 mm; 베이스 간격띄우기: 600 mm; 상단 간격띄우기: -1400 mm; 구조 - 구조: no; 구조적 용도: 비교좌장치; 단면형상 정의 - 단면형상: 수직; 수직 그리드 - 각도: 0 deg; 간격띄우기: 0 mm; 맞춤: 시작; 번호: 4; sets with these values: 2; 치수 - 길이: 15382 mm
기본 벽:A2-22-02A-압출스티로폼, BRACKET(STEEL), ALC블록 (150mm):5900249 | 지상 6층 | 454.8 | 27982 | 2000 | 새 구성 | 벽 | CW112-스테인리스 스틸 커튼월 | 7675291 | 커튼월 | 커튼월: CW112-스테인리스 스틸 커튼월 | 55.964 | CW112-스테인리스 스틸 커튼월 | 2 | ID 데이터 - 마크: 29; 해설: AW; 구속조건 - 매스와 관련됨: no; 룸 경계: yes; 벽 베이스가 부착됩니다.: no; 상단이 부착됩니다.: no; 베이스 구속조건: 지상 6층; 상단 구속조건: 상위 레벨: 지상 7층; 미연결 높이: 2000 mm; 베이스 간격띄우기: 600 mm; 상단 간격띄우기: -1500 mm; 구조 - 구조: no; 구조적 용도: 비교좌장치; 단면형상 정의 - 단면형상: 수직; 수직 그리드 - 각도: 0 deg; 간격띄우기: 0 mm; 맞춤: 시작; 번호: 4; sets with these values: 2; 치수 - 길이: 27982 mm
기본 벽:A2-22-02A-압출스티로폼, BRACKET(STEEL), ALC블록 (150mm):5900255 | 지상 8층 | 454.8 | 27982 | 2000 | 새 구성 | 벽 | CW112-스테인리스 스틸 커튼월 | 7675291 | 커튼월 | 커튼월: CW112-스테인리스 스틸 커튼월 | 55.964 | CW112-스테인리스 스틸 커튼월 | 2 | ID 데이터 - 마크: 29; 해설: AW; 구속조건 - 매스와 관련됨: no; 룸 경계: yes; 벽 베이스가 부착됩니다.: no; 상단이 부착됩니다.: no; 베이스 구속조건: 지상 8층; 상단 구속조건: 상위 레벨: 지상 9층; 미연결 높이: 2000 mm; 베이스 간격띄우기: 600 mm; 상단 간격띄우기: -1500 mm; 구조 - 구조: no; 구조적 용도: 비교좌장치; 단면형상 정의 - 단면형상: 수직; 수직 그리드 - 각도: 0 deg; 간격띄우기: 0 mm; 맞춤: 시작; 번호: 4; sets with these values: 2; 치수 - 길이: 27982 mm
기본 벽:A2-22-02A-압출스티로폼, BRACKET(STEEL), ALC블록 (150mm):5900261 | 지상 10층 | 454.8 | 28000 | 3000 | 새 구성 | 벽 | CW112-스테인리스 스틸 커튼월 | 7675291 | 커튼월 | 커튼월: CW112-스테인리스 스틸 커튼월 | 84 | CW112-스테인리스 스틸 커튼월 | 2 | ID 데이터 - 마크: 29; 해설: AW; 구속조건 - 매스와 관련됨: no; 룸 경계: yes; 벽 베이스가 부착됩니다.: no; 상단이 부착됩니다.: no; 베이스 구속조건: 지상 10층; 상단 구속조건: 상위 레벨: 옥탑층; 미연결 높이: 3000 mm; 베이스 간격띄우기: 600 mm; 상단 간격띄우기: -1400 mm; 구조 - 구조: no; 구조적 용도: 비교좌장치; 단면형상 정의 - 단면형상: 수직; 수직 그리드 - 각도: 0 deg; 간격띄우기: 0 mm; 맞춤: 시작; 번호: 4; sets with these values: 2; 치수 - 길이: 28000 mm
기본 벽:WA211-시멘트벽돌(일반) 벽 (0.5B) 90mm:5909199 | 지상 2층 | 394.8 | 2750 | 3020 | 새 구성 | 벽 | CW112-스테인리스 스틸 커튼월 | 7675291 | 커튼월 | 커튼월: CW112-스테인리스 스틸 커튼월 | 8.305 | CW112-스테인리스 스틸 커튼월 | 2 | ID 데이터 - 마크: 26; 해설: SSD; 구속조건 - 매스와 관련됨: no; 룸 경계: yes; 벽 베이스가 부착됩니다.: no; 상단이 부착됩니다.: no; 베이스 구속조건: 지상 2층; 상단 구속조건: 상위 레벨: 지상 3층; 미연결 높이: 3020 mm; 베이스 간격띄우기: 80 mm; 상단 간격띄우기: -1400 mm; 구조 - 구조: no; 구조적 용도: 비교좌장치; 단면형상 정의 - 단면형상: 수직; 수직 그리드 - 각도: 0 deg; 간격띄우기: 0 mm; 맞춤: 시작; 번호: 4; sets with these values: 2; 치수 - 길이: 2850 mm
기본 벽:WA211-시멘트벽돌(일반) 벽 (0.5B) 90mm:5909199 | 지상 2층 | 394.8 | 6500 | 3020 | 새 구성 | 벽 | CW112-스테인리스 스틸 커튼월 | 7675291 | 커튼월 | 커튼월: CW112-스테인리스 스틸 커튼월 | 19.63 | CW112-스테인리스 스틸 커튼월 | 2 | ID 데이터 - 마크: 27; 해설: SSD; 구속조건 - 매스와 관련됨: no; 룸 경계: yes; 벽 베이스가 부착됩니다.: no; 상단이 부착됩니다.: no; 베이스 구속조건: 지상 2층; 상단 구속조건: 상위 레벨: 지상 3층; 미연결 높이: 3020 mm; 베이스 간격띄우기: 80 mm; 상단 간격띄우기: -1400 mm; 구조 - 구조: no; 구조적 용도: 비교좌장치; 단면형상 정의 - 단면형상: 수직; 수직 그리드 - 각도: 0 deg; 간격띄우기: 0 mm; 맞춤: 시작; 번호: 4; sets with these values: 2; 치수 - 길이: 6500 mm
기본 벽:WA211-시멘트벽돌(일반) 벽 (0.5B) 90mm:5909199 | 지상 2층 | 394.8 | 6600 | 3020 | 새 구성 | 벽 | CW112-스테인리스 스틸 커튼월 | 7675291 | 커튼월 | 커튼월: CW112-스테인리스 스틸 커튼월 | 19.932 | CW112-스테인리스 스틸 커튼월 | 2 | ID 데이터 - 마크: 26; 해설: SSD; 구속조건 - 매스와 관련됨: no; 룸 경계: yes; 벽 베이스가 부착됩니다.: no; 상단이 부착됩니다.: no; 베이스 구속조건: 지상 2층; 상단 구속조건: 상위 레벨: 지상 3층; 미연결 높이: 3020 mm; 베이스 간격띄우기: 80 mm; 상단 간격띄우기: -1400 mm; 구조 - 구조: no; 구조적 용도: 비교좌장치; 단면형상 정의 - 단면형상: 수직; 수직 그리드 - 각도: 0 deg; 간격띄우기: 0 mm; 맞춤: 시작; 번호: 4; sets with these values: 2; 치수 - 길이: 6600 mm
기본 벽:WA211-시멘트벽돌(일반) 벽 (0.5B) 90mm:5909229 | 지상 9층 | 394.8 |  |  | 새 구성 | 벽 | CW112-스테인리스 스틸 커튼월 | 7675291 | 커튼월 | 커튼월: CW112-스테인리스 스틸 커튼월 | 5.1925 | CW112-스테인리스 스틸 커튼월 | 2 | ID 데이터 - 마크: 26; 해설: SSD; 구속조건 - 매스와 관련됨: no; 룸 경계: yes; 벽 베이스가 부착됩니다.: no; 상단이 부착됩니다.: no; 베이스 구속조건: 지상 9층; 상단 구속조건: 상위 레벨: 지상 10층; 미연결 높이: 3020 mm; 베이스 간격띄우기: 80 mm; 상단 간격띄우기: -1400 mm; 구조 - 구조: no; 구조적 용도: 비교좌장치; 단면형상 정의 - 단면형상: 수직; 수직 그리드 - 각도: 0 deg; 간격띄우기: 0 mm; 맞춤: 시작; 번호: 4; sets with these values: 2; 치수 - 길이: 2850 mm; BaseQuantities - Area: 5.1925 m2
기본 벽:(복합)WA211+A1-32-06A-시멘트벽돌(일반)+수성:5909259 | 지상 10층 | 430.8 |  |  | 새 구성 | 벽 | CW112-스테인리스 스틸 커튼월 | 7675291 | 커튼월 | 커튼월: CW112-스테인리스 스틸 커튼월 | 6.50423 | CW112-스테인리스 스틸 커튼월 | 2 | ID 데이터 - 마크: 26; 해설: SSD; 구속조건 - 매스와 관련됨: no; 룸 경계: yes; 벽 베이스가 부착됩니다.: no; 상단이 부착됩니다.: no; 베이스 구속조건: 지상 10층; 상단 구속조건: 상위 레벨: 옥탑층; 미연결 높이: 3520 mm; 베이스 간격띄우기: 80 mm; 상단 간격띄우기: -1400 mm; 구조 - 구조: no; 구조적 용도: 비교좌장치; 단면형상 정의 - 단면형상: 수직; 수직 그리드 - 각도: 0 deg; 간격띄우기: 0 mm; 맞춤: 시작; 번호: 4; sets with these values: 2; 치수 - 길이: 2832.03 mm; BaseQuantities - Area: 6.50423 m2
기본 벽:WA111-철근콘크리트구조 벽 200mm_CW1:5915467 | 지상 1층 | 504.8 | 2020 | 1399.99 | 새 구성 | 벽 | CW112-스테인리스 스틸 커튼월 | 7675291 | 커튼월 | 커튼월: CW112-스테인리스 스틸 커튼월 | 2.82798 | CW112-스테인리스 스틸 커튼월 | 2 | ID 데이터 - 마크: 13; 해설: SSD; 구속조건 - 매스와 관련됨: no; 룸 경계: yes; 벽 베이스가 부착됩니다.: no; 상단이 부착됩니다.: no; 베이스 구속조건: 지상 1층; 상단 구속조건: 상위 레벨: 지상 2층; 미연결 높이: 2020 mm; 베이스 간격띄우기: -470 mm; 상단 간격띄우기: -3250 mm; 구조 - 구조: no; 구조적 용도: 비교좌장치; 단면형상 정의 - 단면형상: 수직; 수직 그리드 - 각도: 0 deg; 간격띄우기: 0 mm; 맞춤: 시작; 번호: 4; sets with these values: 2; 치수 - 길이: 1700 mm
옥상 두겁2:옥상 두겁:6547277:1 | 옥탑층 | 3960 | 400 | 400 |  |  |  |  |  |  |  | 옥상 두겁 | 2
옥상 두겁3:옥상 두겁:6548208:1 | 옥탑층 | 3960 | 400 | 400 |  |  |  |  |  |  |  | 옥상 두겁 | 2
옥상 두겁4:옥상 두겁:6548238:1 | 옥탑층 | 3960 | 400 | 400 |  |  |  |  |  |  |  | 옥상 두겁 | 2
옥상 두겁5:옥상 두겁:6548266:1 | 옥탑층 | 3960 | 400 | 400 |  |  |  |  |  |  |  | 옥상 두겁 | 2
옥상 두겁6:옥상 두겁:6548292:1 | 옥탑층 | 3960 | 400 | 400 |  |  |  |  |  |  |  | 옥상 두겁 | 2
옥상 두겁7:옥상 두겁:6548320:1 | 옥탑층 | 3960 | 400 | 400 |  |  |  |  |  |  |  | 옥상 두겁 | 2
옥상 두겁9:옥상 두겁:6548423:1 | 옥탑층 | 3960 | 400 | 400 |  |  |  |  |  |  |  | 옥상 두겁 | 2
옥상 두겁10:옥상 두겁:6548447:1 | 옥탑층 | 3960 | 400 | 400 |  |  |  |  |  |  |  | 옥상 두겁 | 2
옥상 두겁11:옥상 두겁:6548471:1 | 옥탑층 | 3960 | 400 | 400 |  |  |  |  |  |  |  | 옥상 두겁 | 2
옥상 두겁12:옥상 두겁:6548497:1 | 옥탑층 | 3960 | 400 | 400 |  |  |  |  |  |  |  | 옥상 두겁 | 2
옥상 두겁13:옥상 두겁:6548523:1 | 옥탑층 | 3960 | 400 | 400 |  |  |  |  |  |  |  | 옥상 두겁 | 2
옥상 두겁14:옥상 두겁:6548549:1 | 옥탑층 | 3960 | 400 | 400 |  |  |  |  |  |  |  | 옥상 두겁 | 2
옥상 두겁15:옥상 두겁:6548575:1 | 옥탑층 | 3960 | 400 | 400 |  |  |  |  |  |  |  | 옥상 두겁 | 2
옥상 두겁16:옥상 두겁:6548616:1 | 옥탑층 | 3960 | 400 | 400 |  |  |  |  |  |  |  | 옥상 두겁 | 2
옥상 두겁17:옥상 두겁:6548642:1 | 옥탑층 | 3960 | 400 | 400 |  |  |  |  |  |  |  | 옥상 두겁 | 2
옥상 두겁18:옥상 두겁:6548668:1 | 옥탑층 | 3960 | 400 | 400 |  |  |  |  |  |  |  | 옥상 두겁 | 2
옥상 두겁19:옥상 두겁:6548696:1 | 옥탑층 | 3960 | 400 | 400 |  |  |  |  |  |  |  | 옥상 두겁 | 2
옥상 두겁20:옥상 두겁:6548722:1 | 옥탑층 | 3960 | 400 | 400 |  |  |  |  |  |  |  | 옥상 두겁 | 2
옥상 두겁21:옥상 두겁:6548748:1 | 옥탑층 | 3960 | 400 | 400 |  |  |  |  |  |  |  | 옥상 두겁 | 2
옥상 두겁22:옥상 두겁:6548772:1 | 옥탑층 | 3960 | 400 | 400 |  |  |  |  |  |  |  | 옥상 두겁 | 2
옥상 두겁25:옥상 두겁:6549653:1 | 옥탑층 | 3960 | 400 | 400 |  |  |  |  |  |  |  | 옥상 두겁 | 2
기본 벽:A1-32-06A-콘크리트면정리, 시멘트모르타르(미장용), 수성페인트(내부) (18mm):7555713 | 지상 2층 | 3048 | 1100 | 2100 | 새 구성 | 문 | DR111-외여닫이문(철재, 일반) 1100x2100mm 2 | 8088344 | DR111-외여닫이문(철재, 일반) | DR111-외여닫이문(철재, 일반): DR111-외여닫이문(철재, 일반) 1100x2100mm 2 | 3.66584 | DR111-외여닫이문(철재, 일반) 1100x2100mm 2 | 2 | 구속조건 - 레벨: 지상 2층; 씰 높이: 80 mm; 기타 - 헤드 높이: 2180 mm; 호스트 ID: 2820024; 치수 - 벽체 opening 면적: 2.31 m2; 체적: 0.122657 m3
기본 벽:A1-32-06A-콘크리트면정리, 시멘트모르타르(미장용), 수성페인트(내부) (18mm):7555718 | 지상 2층 | 3048 | 1800 | 2100 | 새 구성 | 문 | DR121-쌍여닫이문(철재, 방화문) 1800x2100mm | 7435628 | DR121-쌍여닫이문(철재, 방화문) | DR121-쌍여닫이문(철재, 방화문): DR121-쌍여닫이문(철재, 방화문) 1800x2100mm | 5.32025 | DR121-쌍여닫이문(철재, 방화문) 1800x2100mm | 2 | 구속조건 - 레벨: 지상 2층; 씰 높이: 80 mm; 기타 - 헤드 높이: 2180 mm; 호스트 ID: 2820050; 치수 - 체적: 0.146498 m3; 데이터 - 벽체 opening 면적: 3.78 m2
기본 벽:A1-32-06A-콘크리트면정리, 시멘트모르타르(미장용), 수성페인트(내부) (18mm):7555718 | 지상 2층 | 322.8 | 2818.01 | 3020 | 새 구성 | 벽 | CW112-스테인리스 스틸 커튼월 | 7675291 | 커튼월 | 커튼월: CW112-스테인리스 스틸 커튼월 | 8.51039 | CW112-스테인리스 스틸 커튼월 | 2 | ID 데이터 - 마크: 29; 해설: SSD; 구속조건 - 매스와 관련됨: no; 룸 경계: yes; 벽 베이스가 부착됩니다.: no; 상단이 부착됩니다.: no; 베이스 구속조건: 지상 2층; 상단 구속조건: 상위 레벨: 지상 3층; 미연결 높이: 3020 mm; 베이스 간격띄우기: 80 mm; 상단 간격띄우기: -1400 mm; 구조 - 구조: no; 구조적 용도: 비교좌장치; 단면형상 정의 - 단면형상: 수직; 수직 그리드 - 각도: 0 deg; 간격띄우기: 0 mm; 맞춤: 시작; 번호: 4; sets with these values: 2; 치수 - 길이: 2818.01 mm
기본 벽:A1-32-06A-콘크리트면정리, 시멘트모르타르(미장용), 수성페인트(내부) (18mm):7555721 | 지상 2층 | 3048 | 900 | 2100 | 새 구성 | 문 | DR111-외여닫이문(철재, 일반) 900x2100mm | 7447208 | DR111-외여닫이문(철재, 일반) | DR111-외여닫이문(철재, 일반): DR111-외여닫이문(철재, 일반) 900x2100mm | 3.19384 | DR111-외여닫이문(철재, 일반) 900x2100mm | 2 | 구속조건 - 레벨: 지상 2층; 씰 높이: 80 mm; 기타 - 헤드 높이: 2180 mm; 호스트 ID: 2820024; 치수 - 벽체 opening 면적: 1.89 m2; 체적: 0.108017 m3
기본 벽:A1-32-06A-콘크리트면정리, 시멘트모르타르(미장용), 수성페인트(내부) (18mm):7555722 | 지상 2층 | 3048 | 600 | 800 | 새 구성 | 창 | WD733-그릴창(알루미늄)_600x800mm | 7459609 | WD733-그릴창(알루미늄) | WD733-그릴창(알루미늄): WD733-그릴창(알루미늄)_600x800mm | 2.12048 | WD733-그릴창(알루미늄)_600x800mm | 2 | 구속조건 - 레벨: 지상 2층; 씰 높이: 500 mm; 기타 - 창의개폐비: 50; 헤드 높이: 1300 mm; 호스트 ID: 2820040; 치수 - 체적: 0.0208362 m3
기본 벽:A1-32-06A-콘크리트면정리, 시멘트모르타르(미장용), 수성페인트(내부) (18mm):7555722 | 지상 2층 | 3048 | 800 | 600 | 새 구성 | 창 | WD733-그릴창(알루미늄)_600x800mm | 7459609 | WD733-그릴창(알루미늄) | WD733-그릴창(알루미늄): WD733-그릴창(알루미늄)_600x800mm | 2.12048 | WD733-그릴창(알루미늄)_600x800mm | 2 | 구속조건 - 레벨: 지상 2층; 씰 높이: 500 mm; 기타 - 창의개폐비: 50; 헤드 높이: 1300 mm; 호스트 ID: 2820040; 치수 - 체적: 0.0208362 m3
기본 벽:A1-32-06A-콘크리트면정리, 시멘트모르타르(미장용), 수성페인트(내부) (18mm):7555723 | 지상 2층 | 3048 | 1100 | 2550 | 새 구성 | 문 | EE111-엘리베이터문(13인승)_1100x2550 | 7620945 | EE111-엘리베이터문(문) | EE111-엘리베이터문(문): EE111-엘리베이터문(13인승)_1100x2550 | 4.15514 | EE111-엘리베이터문(13인승)_1100x2550 | 2 | 구속조건 - 레벨: 지상 2층; 씰 높이: 80 mm; 기타 - 헤드 높이: 2630 mm; 호스트 ID: 2820042; 치수 - 체적: 0.224818 m3
기본 벽:A1-32-06A-콘크리트면정리, 시멘트모르타르(미장용), 수성페인트(내부) (18mm):7555729 | 지상 2층 | 3048 | 2100 | 950 | 새 구성 | 문 | DR111-외여닫이문(유리, 일반, 양개) 950x2100mm | 7685797 | DR111-외여닫이문(철재, 일반, 양개) | DR111-외여닫이문(철재, 일반, 양개): DR111-외여닫이문(유리, 일반, 양개) 950x2100mm | 3.12595 | DR111-외여닫이문(유리, 일반, 양개) 950x2100mm | 2 | 구속조건 - 레벨: 지상 2층; 씰 높이: 80 mm; 기타 - 헤드 높이: 2180 mm; 호스트 ID: 5903096; 치수 - 벽체 opening 면적: 1.995 m2; 체적: 0.0589782 m3
기본 벽:A1-32-06A-콘크리트면정리, 시멘트모르타르(미장용), 수성페인트(내부) (18mm):7555730 | 지상 2층 | 3048 | 1600 | 1500 | 새 구성 | 창 | WD842-2단 하부 더블 프로젝트 창(스테인리스 스틸)_1500x1600mm | 7468499 | WD842-2단 하부 더블 프로젝트 창(스테인리스 스틸) | WD842-2단 하부 더블 프로젝트 창(스테인리스 스틸): WD842-2단 하부 더블 프로젝트 창(스테인리스 스틸)_1500x1600mm | 3.60783 | WD842-2단 하부 더블 프로젝트 창(스테인리스 스틸)_1500x1600mm | 2 | 구속조건 - 레벨: 지상 2층; 씰 높이: 1000 mm; 기타 - 창의개폐비: 100; 헤드 높이: 2600 mm; 호스트 ID: 5998771; 치수 - 체적: 0.084837 m3
기본 벽:A1-32-06A-콘크리트면정리, 시멘트모르타르(미장용), 수성페인트(내부) (18mm):7555737 | 지상 2층 | 322.8 | 3120 | 1200 | 새 구성 | 벽 | CW112-스테인리스 스틸 커튼월 | 7675291 | 커튼월 | 커튼월: CW112-스테인리스 스틸 커튼월 | 3.744 | CW112-스테인리스 스틸 커튼월 | 2 | ID 데이터 - 마크: 0; 해설: AW; 구속조건 - 매스와 관련됨: no; 룸 경계: yes; 벽 베이스가 부착됩니다.: no; 상단이 부착됩니다.: no; 베이스 구속조건: 지상 2층; 상단 구속조건: 상위 레벨: 지상 3층; 미연결 높이: 3120 mm; 베이스 간격띄우기: 80 mm; 상단 간격띄우기: -1300 mm; 구조 - 구조: no; 구조적 용도: 비교좌장치; 단면형상 정의 - 단면형상: 수직; 수직 그리드 - 각도: 0 deg; 간격띄우기: 0 mm; 맞춤: 시작; 번호: 4; sets with these values: 2; 치수 - 길이: 1200 mm
기본 벽:A1-32-06A-콘크리트면정리, 시멘트모르타르(미장용), 수성페인트(내부) (18mm):7555737 | 지상 2층 | 3048 | 2000 | 1800 | 새 구성 | 창 | WD842-2단 하부 더블 프로젝트 창(스테인리스 스틸)_2000x1800mm | 7468501 | WD842-2단 하부 더블 프로젝트 창(스테인리스 스틸) | WD842-2단 하부 더블 프로젝트 창(스테인리스 스틸): WD842-2단 하부 더블 프로젝트 창(스테인리스 스틸)_2000x1800mm | 5.10973 | WD842-2단 하부 더블 프로젝트 창(스테인리스 스틸)_2000x1800mm | 2 | 구속조건 - 레벨: 지상 2층; 씰 높이: 1000 mm; 기타 - 창의개폐비: 100; 헤드 높이: 2800 mm; 호스트 ID: 2820046; 치수 - 체적: 0.113019 m3
기본 벽:A1-32-06A-콘크리트면정리, 시멘트모르타르(미장용), 수성페인트(내부) (18mm):7555738 | 지상 2층 | 322.8 | 3020 | 2750 | 새 구성 | 벽 | CW112-스테인리스 스틸 커튼월 | 7675291 | 커튼월 | 커튼월: CW112-스테인리스 스틸 커튼월 | 8.305 | CW112-스테인리스 스틸 커튼월 | 2 | ID 데이터 - 마크: 26; 해설: SSD; 구속조건 - 매스와 관련됨: no; 룸 경계: yes; 벽 베이스가 부착됩니다.: no; 상단이 부착됩니다.: no; 베이스 구속조건: 지상 2층; 상단 구속조건: 상위 레벨: 지상 3층; 미연결 높이: 3020 mm; 베이스 간격띄우기: 80 mm; 상단 간격띄우기: -1400 mm; 구조 - 구조: no; 구조적 용도: 비교좌장치; 단면형상 정의 - 단면형상: 수직; 수직 그리드 - 각도: 0 deg; 간격띄우기: 0 mm; 맞춤: 시작; 번호: 4; sets with these values: 2; 치수 - 길이: 2850 mm
기본 벽:A1-32-06A-콘크리트면정리, 시멘트모르타르(미장용), 수성페인트(내부) (18mm):7555738 | 지상 2층 | 322.8 | 3020 | 6600 | 새 구성 | 벽 | CW112-스테인리스 스틸 커튼월 | 7675291 | 커튼월 | 커튼월: CW112-스테인리스 스틸 커튼월 | 19.932 | CW112-스테인리스 스틸 커튼월 | 2 | ID 데이터 - 마크: 26; 해설: SSD; 구속조건 - 매스와 관련됨: no; 룸 경계: yes; 벽 베이스가 부착됩니다.: no; 상단이 부착됩니다.: no; 베이스 구속조건: 지상 2층; 상단 구속조건: 상위 레벨: 지상 3층; 미연결 높이: 3020 mm; 베이스 간격띄우기: 80 mm; 상단 간격띄우기: -1400 mm; 구조 - 구조: no; 구조적 용도: 비교좌장치; 단면형상 정의 - 단면형상: 수직; 수직 그리드 - 각도: 0 deg; 간격띄우기: 0 mm; 맞춤: 시작; 번호: 4; sets with these values: 2; 치수 - 길이: 6600 mm
기본 벽:A1-32-06A-콘크리트면정리, 시멘트모르타르(미장용), 수성페인트(내부) (18mm):7555738 | 지상 2층 | 322.8 | 3020 | 6500 | 새 구성 | 벽 | CW112-스테인리스 스틸 커튼월 | 7675291 | 커튼월 | 커튼월: CW112-스테인리스 스틸 커튼월 | 19.63 | CW112-스테인리스 스틸 커튼월 | 2 | ID 데이터 - 마크: 27; 해설: SSD; 구속조건 - 매스와 관련됨: no; 룸 경계: yes; 벽 베이스가 부착됩니다.: no; 상단이 부착됩니다.: no; 베이스 구속조건: 지상 2층; 상단 구속조건: 상위 레벨: 지상 3층; 미연결 높이: 3020 mm; 베이스 간격띄우기: 80 mm; 상단 간격띄우기: -1400 mm; 구조 - 구조: no; 구조적 용도: 비교좌장치; 단면형상 정의 - 단면형상: 수직; 수직 그리드 - 각도: 0 deg; 간격띄우기: 0 mm; 맞춤: 시작; 번호: 4; sets with these values: 2; 치수 - 길이: 6500 mm
기본 벽:A1-32-06A-콘크리트면정리, 시멘트모르타르(미장용), 수성페인트(내부) (18mm):7555741 | 지상 2층 | 322.8 | 3120 | 1200 | 새 구성 | 벽 | CW112-스테인리스 스틸 커튼월 | 7675291 | 커튼월 | 커튼월: CW112-스테인리스 스틸 커튼월 | 3.744 | CW112-스테인리스 스틸 커튼월 | 2 | ID 데이터 - 마크: 0; 해설: AW; 구속조건 - 매스와 관련됨: no; 룸 경계: yes; 벽 베이스가 부착됩니다.: no; 상단이 부착됩니다.: no; 베이스 구속조건: 지상 2층; 상단 구속조건: 상위 레벨: 지상 3층; 미연결 높이: 3120 mm; 베이스 간격띄우기: 80 mm; 상단 간격띄우기: -1300 mm; 구조 - 구조: no; 구조적 용도: 비교좌장치; 단면형상 정의 - 단면형상: 수직; 수직 그리드 - 각도: 0 deg; 간격띄우기: 0 mm; 맞춤: 시작; 번호: 4; sets with these values: 2; 치수 - 길이: 1200 mm
기본 벽:A1-32-06A-콘크리트면정리, 시멘트모르타르(미장용), 수성페인트(내부) (18mm):7555755 | 지상 2층 | 322.8 | 3020 | 2750 | 새 구성 | 벽 | CW112-스테인리스 스틸 커튼월 | 7675291 | 커튼월 | 커튼월: CW112-스테인리스 스틸 커튼월 | 8.305 | CW112-스테인리스 스틸 커튼월 | 2 | ID 데이터 - 마크: 26; 해설: SSD; 구속조건 - 매스와 관련됨: no; 룸 경계: yes; 벽 베이스가 부착됩니다.: no; 상단이 부착됩니다.: no; 베이스 구속조건: 지상 2층; 상단 구속조건: 상위 레벨: 지상 3층; 미연결 높이: 3020 mm; 베이스 간격띄우기: 80 mm; 상단 간격띄우기: -1400 mm; 구조 - 구조: no; 구조적 용도: 비교좌장치; 단면형상 정의 - 단면형상: 수직; 수직 그리드 - 각도: 0 deg; 간격띄우기: 0 mm; 맞춤: 시작; 번호: 4; sets with these values: 2; 치수 - 길이: 2850 mm
기본 벽:A1-32-06A-콘크리트면정리, 시멘트모르타르(미장용), 수성페인트(내부) (18mm):7555755 | 지상 2층 | 322.8 | 3020 | 6500 | 새 구성 | 벽 | CW112-스테인리스 스틸 커튼월 | 7675291 | 커튼월 | 커튼월: CW112-스테인리스 스틸 커튼월 | 19.63 | CW112-스테인리스 스틸 커튼월 | 2 | ID 데이터 - 마크: 27; 해설: SSD; 구속조건 - 매스와 관련됨: no; 룸 경계: yes; 벽 베이스가 부착됩니다.: no; 상단이 부착됩니다.: no; 베이스 구속조건: 지상 2층; 상단 구속조건: 상위 레벨: 지상 3층; 미연결 높이: 3020 mm; 베이스 간격띄우기: 80 mm; 상단 간격띄우기: -1400 mm; 구조 - 구조: no; 구조적 용도: 비교좌장치; 단면형상 정의 - 단면형상: 수직; 수직 그리드 - 각도: 0 deg; 간격띄우기: 0 mm; 맞춤: 시작; 번호: 4; sets with these values: 2; 치수 - 길이: 6500 mm
기본 벽:A1-32-06A-콘크리트면정리, 시멘트모르타르(미장용), 수성페인트(내부) (18mm):7555755 | 지상 2층 | 322.8 | 3020 | 6600 | 새 구성 | 벽 | CW112-스테인리스 스틸 커튼월 | 7675291 | 커튼월 | 커튼월: CW112-스테인리스 스틸 커튼월 | 19.932 | CW112-스테인리스 스틸 커튼월 | 2 | ID 데이터 - 마크: 26; 해설: SSD; 구속조건 - 매스와 관련됨: no; 룸 경계: yes; 벽 베이스가 부착됩니다.: no; 상단이 부착됩니다.: no; 베이스 구속조건: 지상 2층; 상단 구속조건: 상위 레벨: 지상 3층; 미연결 높이: 3020 mm; 베이스 간격띄우기: 80 mm; 상단 간격띄우기: -1400 mm; 구조 - 구조: no; 구조적 용도: 비교좌장치; 단면형상 정의 - 단면형상: 수직; 수직 그리드 - 각도: 0 deg; 간격띄우기: 0 mm; 맞춤: 시작; 번호: 4; sets with these values: 2; 치수 - 길이: 6600 mm
기본 벽:A1-32-06A-콘크리트면정리, 시멘트모르타르(미장용), 수성페인트(내부) (18mm):7555757 | 지상 2층 | 322.8 | 6500 | 3020 | 새 구성 | 벽 | CW112-스테인리스 스틸 커튼월 | 7675291 | 커튼월 | 커튼월: CW112-스테인리스 스틸 커튼월 | 19.63 | CW112-스테인리스 스틸 커튼월 | 2 | ID 데이터 - 마크: 27; 해설: SSD; 구속조건 - 매스와 관련됨: no; 룸 경계: yes; 벽 베이스가 부착됩니다.: no; 상단이 부착됩니다.: no; 베이스 구속조건: 지상 2층; 상단 구속조건: 상위 레벨: 지상 3층; 미연결 높이: 3020 mm; 베이스 간격띄우기: 80 mm; 상단 간격띄우기: -1400 mm; 구조 - 구조: no; 구조적 용도: 비교좌장치; 단면형상 정의 - 단면형상: 수직; 수직 그리드 - 각도: 0 deg; 간격띄우기: 0 mm; 맞춤: 시작; 번호: 4; sets with these values: 2; 치수 - 길이: 6500 mm
기본 벽:A1-32-06A-콘크리트면정리, 시멘트모르타르(미장용), 수성페인트(내부) (18mm):7555757 | 지상 2층 | 322.8 | 2750 | 3020 | 새 구성 | 벽 | CW112-스테인리스 스틸 커튼월 | 7675291 | 커튼월 | 커튼월: CW112-스테인리스 스틸 커튼월 | 8.305 | CW112-스테인리스 스틸 커튼월 | 2 | ID 데이터 - 마크: 26; 해설: SSD; 구속조건 - 매스와 관련됨: no; 룸 경계: yes; 벽 베이스가 부착됩니다.: no; 상단이 부착됩니다.: no; 베이스 구속조건: 지상 2층; 상단 구속조건: 상위 레벨: 지상 3층; 미연결 높이: 3020 mm; 베이스 간격띄우기: 80 mm; 상단 간격띄우기: -1400 mm; 구조 - 구조: no; 구조적 용도: 비교좌장치; 단면형상 정의 - 단면형상: 수직; 수직 그리드 - 각도: 0 deg; 간격띄우기: 0 mm; 맞춤: 시작; 번호: 4; sets with these values: 2; 치수 - 길이: 2850 mm
기본 벽:A1-32-06A-콘크리트면정리, 시멘트모르타르(미장용), 수성페인트(내부) (18mm):7555757 | 지상 2층 | 322.8 | 6600 | 3020 | 새 구성 | 벽 | CW112-스테인리스 스틸 커튼월 | 7675291 | 커튼월 | 커튼월: CW112-스테인리스 스틸 커튼월 | 19.932 | CW112-스테인리스 스틸 커튼월 | 2 | ID 데이터 - 마크: 26; 해설: SSD; 구속조건 - 매스와 관련됨: no; 룸 경계: yes; 벽 베이스가 부착됩니다.: no; 상단이 부착됩니다.: no; 베이스 구속조건: 지상 2층; 상단 구속조건: 상위 레벨: 지상 3층; 미연결 높이: 3020 mm; 베이스 간격띄우기: 80 mm; 상단 간격띄우기: -1400 mm; 구조 - 구조: no; 구조적 용도: 비교좌장치; 단면형상 정의 - 단면형상: 수직; 수직 그리드 - 각도: 0 deg; 간격띄우기: 0 mm; 맞춤: 시작; 번호: 4; sets with these values: 2; 치수 - 길이: 6600 mm
기본 벽:A1-32-06A-콘크리트면정리, 시멘트모르타르(미장용), 수성페인트(내부) (18mm):7555764 | 지상 2층 | 322.8 | 3020 | 2499.97 | 새 구성 | 벽 | CW112-스테인리스 스틸 커튼월 | 7675291 | 커튼월 | 커튼월: CW112-스테인리스 스틸 커튼월 | 7.54992 | CW112-스테인리스 스틸 커튼월 | 2 | ID 데이터 - 마크: 25; 해설: SSD; 구속조건 - 매스와 관련됨: no; 룸 경계: yes; 벽 베이스가 부착됩니다.: no; 상단이 부착됩니다.: no; 베이스 구속조건: 지상 2층; 상단 구속조건: 상위 레벨: 지상 3층; 미연결 높이: 3020 mm; 베이스 간격띄우기: 80 mm; 상단 간격띄우기: -1400 mm; 구조 - 구조: no; 구조적 용도: 비교좌장치; 단면형상 정의 - 단면형상: 수직; 수직 그리드 - 각도: 0 deg; 간격띄우기: 0 mm; 맞춤: 시작; 번호: 4; sets with these values: 2; 치수 - 길이: 2499.97 mm
기본 벽:A1-32-06A-콘크리트면정리, 시멘트모르타르(미장용), 수성페인트(내부) (18mm):7555764 | 지상 2층 | 322.8 | 9900 | 3020 | 새 구성 | 벽 | CW112-스테인리스 스틸 커튼월 | 7675291 | 커튼월 | 커튼월: CW112-스테인리스 스틸 커튼월 | 29.898 | CW112-스테인리스 스틸 커튼월 | 2 | ID 데이터 - 마크: 28; 해설: SSD; 구속조건 - 매스와 관련됨: no; 룸 경계: yes; 벽 베이스가 부착됩니다.: no; 상단이 부착됩니다.: no; 베이스 구속조건: 지상 2층; 상단 구속조건: 상위 레벨: 지상 3층; 미연결 높이: 3020 mm; 베이스 간격띄우기: 80 mm; 상단 간격띄우기: -1400 mm; 구조 - 구조: no; 구조적 용도: 비교좌장치; 단면형상 정의 - 단면형상: 수직; 수직 그리드 - 각도: 0 deg; 간격띄우기: 0 mm; 맞춤: 시작; 번호: 4; sets with these values: 2; 치수 - 길이: 9900 mm
기본 벽:A1-32-06A-콘크리트면정리, 시멘트모르타르(미장용), 수성페인트(내부) (18mm):7555764 | 지상 2층 | 322.8 | 2218 | 3020 | 새 구성 | 벽 | CW112-스테인리스 스틸 커튼월 | 7675291 | 커튼월 | 커튼월: CW112-스테인리스 스틸 커튼월 | 6.69836 | CW112-스테인리스 스틸 커튼월 | 2 | ID 데이터 - 마크: 29; 해설: SSD; 구속조건 - 매스와 관련됨: no; 룸 경계: yes; 벽 베이스가 부착됩니다.: no; 상단이 부착됩니다.: no; 베이스 구속조건: 지상 2층; 상단 구속조건: 상위 레벨: 지상 3층; 미연결 높이: 3020 mm; 베이스 간격띄우기: 80 mm; 상단 간격띄우기: -1400 mm; 구조 - 구조: no; 구조적 용도: 비교좌장치; 단면형상 정의 - 단면형상: 수직; 수직 그리드 - 각도: 0 deg; 간격띄우기: 0 mm; 맞춤: 시작; 번호: 4; sets with these values: 2; 치수 - 길이: 2218 mm
기본 벽:A1-32-06A-콘크리트면정리, 시멘트모르타르(미장용), 수성페인트(내부) (18mm):7555773 | 지상 2층 | 322.8 | 9900 | 3020 | 새 구성 | 벽 | CW112-스테인리스 스틸 커튼월 | 7675291 | 커튼월 | 커튼월: CW112-스테인리스 스틸 커튼월 | 29.898 | CW112-스테인리스 스틸 커튼월 | 2 | ID 데이터 - 마크: 28; 해설: SSD; 구속조건 - 매스와 관련됨: no; 룸 경계: yes; 벽 베이스가 부착됩니다.: no; 상단이 부착됩니다.: no; 베이스 구속조건: 지상 2층; 상단 구속조건: 상위 레벨: 지상 3층; 미연결 높이: 3020 mm; 베이스 간격띄우기: 80 mm; 상단 간격띄우기: -1400 mm; 구조 - 구조: no; 구조적 용도: 비교좌장치; 단면형상 정의 - 단면형상: 수직; 수직 그리드 - 각도: 0 deg; 간격띄우기: 0 mm; 맞춤: 시작; 번호: 4; sets with these values: 2; 치수 - 길이: 9900 mm
기본 벽:A1-32-06A-콘크리트면정리, 시멘트모르타르(미장용), 수성페인트(내부) (18mm):7555773 | 지상 2층 | 322.8 | 3020 | 2499.97 | 새 구성 | 벽 | CW112-스테인리스 스틸 커튼월 | 7675291 | 커튼월 | 커튼월: CW112-스테인리스 스틸 커튼월 | 7.54992 | CW112-스테인리스 스틸 커튼월 | 2 | ID 데이터 - 마크: 25; 해설: SSD; 구속조건 - 매스와 관련됨: no; 룸 경계: yes; 벽 베이스가 부착됩니다.: no; 상단이 부착됩니다.: no; 베이스 구속조건: 지상 2층; 상단 구속조건: 상위 레벨: 지상 3층; 미연결 높이: 3020 mm; 베이스 간격띄우기: 80 mm; 상단 간격띄우기: -1400 mm; 구조 - 구조: no; 구조적 용도: 비교좌장치; 단면형상 정의 - 단면형상: 수직; 수직 그리드 - 각도: 0 deg; 간격띄우기: 0 mm; 맞춤: 시작; 번호: 4; sets with these values: 2; 치수 - 길이: 2499.97 mm
기본 벽:A1-32-06A-콘크리트면정리, 시멘트모르타르(미장용), 수성페인트(내부) (18mm):7555773 | 지상 2층 | 322.8 | 2218 | 3020 | 새 구성 | 벽 | CW112-스테인리스 스틸 커튼월 | 7675291 | 커튼월 | 커튼월: CW112-스테인리스 스틸 커튼월 | 6.69836 | CW112-스테인리스 스틸 커튼월 | 2 | ID 데이터 - 마크: 29; 해설: SSD; 구속조건 - 매스와 관련됨: no; 룸 경계: yes; 벽 베이스가 부착됩니다.: no; 상단이 부착됩니다.: no; 베이스 구속조건: 지상 2층; 상단 구속조건: 상위 레벨: 지상 3층; 미연결 높이: 3020 mm; 베이스 간격띄우기: 80 mm; 상단 간격띄우기: -1400 mm; 구조 - 구조: no; 구조적 용도: 비교좌장치; 단면형상 정의 - 단면형상: 수직; 수직 그리드 - 각도: 0 deg; 간격띄우기: 0 mm; 맞춤: 시작; 번호: 4; sets with these values: 2; 치수 - 길이: 2218 mm
기본 벽:A1-32-06A-콘크리트면정리, 시멘트모르타르(미장용), 수성페인트(내부) (18mm):7555779 | 지상 2층 | 322.8 | 2218 | 3020 | 새 구성 | 벽 | CW112-스테인리스 스틸 커튼월 | 7675291 | 커튼월 | 커튼월: CW112-스테인리스 스틸 커튼월 | 6.69836 | CW112-스테인리스 스틸 커튼월 | 2 | ID 데이터 - 마크: 29; 해설: SSD; 구속조건 - 매스와 관련됨: no; 룸 경계: yes; 벽 베이스가 부착됩니다.: no; 상단이 부착됩니다.: no; 베이스 구속조건: 지상 2층; 상단 구속조건: 상위 레벨: 지상 3층; 미연결 높이: 3020 mm; 베이스 간격띄우기: 80 mm; 상단 간격띄우기: -1400 mm; 구조 - 구조: no; 구조적 용도: 비교좌장치; 단면형상 정의 - 단면형상: 수직; 수직 그리드 - 각도: 0 deg; 간격띄우기: 0 mm; 맞춤: 시작; 번호: 4; sets with these values: 2; 치수 - 길이: 2218 mm
기본 벽:A1-32-06A-콘크리트면정리, 시멘트모르타르(미장용), 수성페인트(내부) (18mm):7555779 | 지상 2층 | 322.8 | 3020 | 2499.97 | 새 구성 | 벽 | CW112-스테인리스 스틸 커튼월 | 7675291 | 커튼월 | 커튼월: CW112-스테인리스 스틸 커튼월 | 7.54992 | CW112-스테인리스 스틸 커튼월 | 2 | ID 데이터 - 마크: 25; 해설: SSD; 구속조건 - 매스와 관련됨: no; 룸 경계: yes; 벽 베이스가 부착됩니다.: no; 상단이 부착됩니다.: no; 베이스 구속조건: 지상 2층; 상단 구속조건: 상위 레벨: 지상 3층; 미연결 높이: 3020 mm; 베이스 간격띄우기: 80 mm; 상단 간격띄우기: -1400 mm; 구조 - 구조: no; 구조적 용도: 비교좌장치; 단면형상 정의 - 단면형상: 수직; 수직 그리드 - 각도: 0 deg; 간격띄우기: 0 mm; 맞춤: 시작; 번호: 4; sets with these values: 2; 치수 - 길이: 2499.97 mm
기본 벽:A1-32-06A-콘크리트면정리, 시멘트모르타르(미장용), 수성페인트(내부) (18mm):7555779 | 지상 2층 | 322.8 | 9900 | 3020 | 새 구성 | 벽 | CW112-스테인리스 스틸 커튼월 | 7675291 | 커튼월 | 커튼월: CW112-스테인리스 스틸 커튼월 | 29.898 | CW112-스테인리스 스틸 커튼월 | 2 | ID 데이터 - 마크: 28; 해설: SSD; 구속조건 - 매스와 관련됨: no; 룸 경계: yes; 벽 베이스가 부착됩니다.: no; 상단이 부착됩니다.: no; 베이스 구속조건: 지상 2층; 상단 구속조건: 상위 레벨: 지상 3층; 미연결 높이: 3020 mm; 베이스 간격띄우기: 80 mm; 상단 간격띄우기: -1400 mm; 구조 - 구조: no; 구조적 용도: 비교좌장치; 단면형상 정의 - 단면형상: 수직; 수직 그리드 - 각도: 0 deg; 간격띄우기: 0 mm; 맞춤: 시작; 번호: 4; sets with these values: 2; 치수 - 길이: 9900 mm
기본 벽:A1-32-06A-콘크리트면정리, 시멘트모르타르(미장용), 수성페인트(내부) (18mm):7555780 | 지상 2층 | 322.8 | 2720.98 | 3020 | 새 구성 | 벽 | CW112-스테인리스 스틸 커튼월 | 7675291 | 커튼월 | 커튼월: CW112-스테인리스 스틸 커튼월 | 8.21737 | CW112-스테인리스 스틸 커튼월 | 2 | ID 데이터 - 마크: 29; 해설: SSD; 구속조건 - 매스와 관련됨: no; 룸 경계: yes; 벽 베이스가 부착됩니다.: no; 상단이 부착됩니다.: no; 베이스 구속조건: 지상 2층; 상단 구속조건: 상위 레벨: 지상 3층; 미연결 높이: 3020 mm; 베이스 간격띄우기: 80 mm; 상단 간격띄우기: -1400 mm; 구조 - 구조: no; 구조적 용도: 비교좌장치; 단면형상 정의 - 단면형상: 수직; 수직 그리드 - 각도: 0 deg; 간격띄우기: 0 mm; 맞춤: 시작; 번호: 4; sets with these values: 2; 치수 - 길이: 2720.98 mm
기본 벽:A1-32-06A-콘크리트면정리, 시멘트모르타르(미장용), 수성페인트(내부) (18mm):7555812 | 지상 2층 | 3048 | 950 | 2100 | 새 구성 | 문 | DR111-외여닫이문(유리, 일반, 양개) 950x2100mm | 7685797 | DR111-외여닫이문(철재, 일반, 양개) | DR111-외여닫이문(철재, 일반, 양개): DR111-외여닫이문(유리, 일반, 양개) 950x2100mm | 3.12595 | DR111-외여닫이문(유리, 일반, 양개) 950x2100mm | 2 | 구속조건 - 레벨: 지상 2층; 씰 높이: 80 mm; 기타 - 헤드 높이: 2180 mm; 호스트 ID: 5903096; 치수 - 벽체 opening 면적: 1.995 m2; 체적: 0.0589782 m3
기본 벽:A1-32-06A-콘크리트면정리, 시멘트모르타르(미장용), 수성페인트(내부) (18mm):7555817 | 지상 2층 | 3048 | 1000 | 2100 | 새 구성 | 문 | DR111-외여닫이문(철재, 일반)_유리포함 (원형)_2100x1000 | 7452354 | DR111-외여닫이문(철재,일반)_유리포함(원형) | DR111-외여닫이문(철재,일반)_유리포함(원형): DR111-외여닫이문(철재, 일반)_유리포함 (원형)_2100x1000 | 3.71966 | DR111-외여닫이문(철재, 일반)_유리포함 (원형)_2100x1000 | 2 | 구속조건 - 레벨: 지상 2층; 씰 높이: 80 mm; 기타 - 헤드 높이: 2180 mm; 호스트 ID: 2820060; 치수 - 체적: 0.116207 m3
기본 벽:A1-32-06A-콘크리트면정리, 시멘트모르타르(미장용), 수성페인트(내부) (18mm):7555817 | 지상 2층 | 3048 | 600 | 650 | 새 구성 | 문 | DR872-샤프트 점검구(스테인리스 스틸)_650x600 | 3614979 | DR872-샤프트 점검구(스테인리스 스틸) | DR872-샤프트 점검구(스테인리스 스틸): DR872-샤프트 점검구(스테인리스 스틸)_650x600 | 0.851649 | DR872-샤프트 점검구(스테인리스 스틸)_650x600 | 2 | 구속조건 - 레벨: 지상 2층; 씰 높이: 1200 mm; 기타 - 헤드 높이: 1800 mm; 호스트 ID: 2820052; 치수 - 체적: 0.0317935 m3
기본 벽:A1-32-06A-콘크리트면정리, 시멘트모르타르(미장용), 수성페인트(내부) (18mm):7555819 | 지상 2층 | 3048 | 2100 | 1000 | 새 구성 | 문 | DR111-외여닫이문(철재, 일반)_유리포함 (원형)_2100x1000 | 7452354 | DR111-외여닫이문(철재,일반)_유리포함(원형) | DR111-외여닫이문(철재,일반)_유리포함(원형): DR111-외여닫이문(철재, 일반)_유리포함 (원형)_2100x1000 | 3.71966 | DR111-외여닫이문(철재, 일반)_유리포함 (원형)_2100x1000 | 2 | 구속조건 - 레벨: 지상 2층; 씰 높이: 80 mm; 기타 - 헤드 높이: 2180 mm; 호스트 ID: 2820028; 치수 - 체적: 0.116207 m3
기본 벽:A1-32-06A-콘크리트면정리, 시멘트모르타르(미장용), 수성페인트(내부) (18mm):7555821 | 지상 2층 | 3048 | 1600 | 650 | 새 구성 | 문 | DR872-샤프트 점검구(스테인리스 스틸)_650x1600 | 3648337 | DR872-샤프트 점검구(스테인리스 스틸) | DR872-샤프트 점검구(스테인리스 스틸): DR872-샤프트 점검구(스테인리스 스틸)_650x1600 | 1.90665 | DR872-샤프트 점검구(스테인리스 스틸)_650x1600 | 2 | 구속조건 - 레벨: 지상 2층; 씰 높이: 80 mm; 기타 - 헤드 높이: 1680 mm; 호스트 ID: 2820048; 치수 - 체적: 0.0736435 m3
2 x 기본 벽:A1-32-06A-콘크리트면정리, 시멘트모르타르(미장용), 수성페인트(내부) (18mm):7555822 | 지상 2층 | 3048 | 2550 | 1100 | 새 구성 | 문 | EE111-엘리베이터문(20인승)_1100x2550 | 7620949 | EE111-엘리베이터문(문) | EE111-엘리베이터문(문): EE111-엘리베이터문(20인승)_1100x2550 | 4.15514 | EE111-엘리베이터문(20인승)_1100x2550 | 2 | 구속조건 - 레벨: 지상 2층; 씰 높이: 80 mm; 기타 - 헤드 높이: 2630 mm; 호스트 ID: 2820026; 치수 - 체적: 0.224818 m3
기본 벽:A1-32-06A-콘크리트면정리, 시멘트모르타르(미장용), 수성페인트(내부) (18mm):7555823 | 지상 2층 | 3048 | 900 | 2100 | 새 구성 | 문 | DR111-외여닫이문(철재, 일반) 900x2100mm | 7447208 | DR111-외여닫이문(철재, 일반) | DR111-외여닫이문(철재, 일반): DR111-외여닫이문(철재, 일반) 900x2100mm | 3.19384 | DR111-외여닫이문(철재, 일반) 900x2100mm | 2 | 구속조건 - 레벨: 지상 2층; 씰 높이: 80 mm; 기타 - 헤드 높이: 2180 mm; 호스트 ID: 2820024; 치수 - 벽체 opening 면적: 1.89 m2; 체적: 0.108017 m3
기본 벽:A1-32-06A-콘크리트면정리, 시멘트모르타르(미장용), 수성페인트(내부) (18mm):7555823 | 지상 2층 | 3048 | 1100 | 2100 | 새 구성 | 문 | DR111-외여닫이문(철재, 일반) 1100x2100mm 2 | 8088344 | DR111-외여닫이문(철재, 일반) | DR111-외여닫이문(철재, 일반): DR111-외여닫이문(철재, 일반) 1100x2100mm 2 | 3.66584 | DR111-외여닫이문(철재, 일반) 1100x2100mm 2 | 2 | 구속조건 - 레벨: 지상 2층; 씰 높이: 80 mm; 기타 - 헤드 높이: 2180 mm; 호스트 ID: 2820024; 치수 - 벽체 opening 면적: 2.31 m2; 체적: 0.122657 m3
기본 벽:A1-32-06A-콘크리트면정리, 시멘트모르타르(미장용), 수성페인트(내부) (18mm):7555823 | 지상 2층 | 3048 | 1600 | 650 | 새 구성 | 문 | DR872-샤프트 점검구(스테인리스 스틸)_650x1600 | 3648337 | DR872-샤프트 점검구(스테인리스 스틸) | DR872-샤프트 점검구(스테인리스 스틸): DR872-샤프트 점검구(스테인리스 스틸)_650x1600 | 1.90665 | DR872-샤프트 점검구(스테인리스 스틸)_650x1600 | 2 | 구속조건 - 레벨: 지상 2층; 씰 높이: 80 mm; 기타 - 헤드 높이: 1680 mm; 호스트 ID: 2820024; 치수 - 체적: 0.0736435 m3
기본 벽:A1-32-06A-콘크리트면정리, 시멘트모르타르(미장용), 수성페인트(내부) (18mm):7557724:1 | 지상 3층 | 3200 | 5482 | 17.739 |  |  |  |  |  |  |  | A1-32-06A-콘크리트면정리, 시멘트모르타르(미장용), 수성페인트(내부) (18mm) | 2
기본 벽:A1-32-06A-콘크리트면정리, 시멘트모르타르(미장용), 수성페인트(내부) (18mm):7557729 | 지상 3층 | 3048 | 1800 | 2100 | 새 구성 | 문 | DR121-쌍여닫이문(철재, 방화문) 1800x2100mm | 7435628 | DR121-쌍여닫이문(철재, 방화문) | DR121-쌍여닫이문(철재, 방화문): DR121-쌍여닫이문(철재, 방화문) 1800x2100mm | 5.32025 | DR121-쌍여닫이문(철재, 방화문) 1800x2100mm | 2 | 구속조건 - 레벨: 지상 3층; 씰 높이: 80 mm; 기타 - 헤드 높이: 2180 mm; 호스트 ID: 2820467; 치수 - 체적: 0.146498 m3; 데이터 - 벽체 opening 면적: 3.78 m2
기본 벽:A1-32-06A-콘크리트면정리, 시멘트모르타르(미장용), 수성페인트(내부) (18mm):7557729 | 지상 3층 | 322.8 | 2850 | 2620 | 새 구성 | 벽 | CW112-스테인리스 스틸 커튼월 | 7675291 | 커튼월 | 커튼월: CW112-스테인리스 스틸 커튼월 | 7.467 | CW112-스테인리스 스틸 커튼월 | 2 | ID 데이터 - 해설: SSD; 구속조건 - 매스와 관련됨: no; 룸 경계: yes; 벽 베이스가 부착됩니다.: no; 상단이 부착됩니다.: no; 베이스 구속조건: 지상 3층; 상단 구속조건: 상위 레벨: 지상 4층; 미연결 높이: 2620 mm; 베이스 간격띄우기: 80 mm; 상단 간격띄우기: -1400 mm; 구조 - 구조: no; 구조적 용도: 비교좌장치; 단면형상 정의 - 단면형상: 수직; 수직 그리드 - 각도: 0 deg; 간격띄우기: 0 mm; 맞춤: 시작; 번호: 4; sets with these values: 2; 치수 - 길이: 2850 mm
기본 벽:A1-32-06A-콘크리트면정리, 시멘트모르타르(미장용), 수성페인트(내부) (18mm):7557732 | 지상 3층 | 3048 | 900 | 2100 | 새 구성 | 문 | DR111-외여닫이문(철재, 일반) 900x2100mm | 7447208 | DR111-외여닫이문(철재, 일반) | DR111-외여닫이문(철재, 일반): DR111-외여닫이문(철재, 일반) 900x2100mm | 3.19384 | DR111-외여닫이문(철재, 일반) 900x2100mm | 2 | 구속조건 - 레벨: 지상 3층; 씰 높이: 80 mm; 기타 - 헤드 높이: 2180 mm; 호스트 ID: 2820443; 치수 - 벽체 opening 면적: 1.89 m2; 체적: 0.108017 m3
기본 벽:A1-32-06A-콘크리트면정리, 시멘트모르타르(미장용), 수성페인트(내부) (18mm):7557740 | 지상 3층 | 3048 | 2100 | 900 | 새 구성 | 문 | DR111-외여닫이문(철재, 일반) 900x2100mm | 7447208 | DR111-외여닫이문(철재, 일반) | DR111-외여닫이문(철재, 일반): DR111-외여닫이문(철재, 일반) 900x2100mm | 3.19384 | DR111-외여닫이문(철재, 일반) 900x2100mm | 2 | 구속조건 - 레벨: 지상 3층; 씰 높이: 80 mm; 기타 - 헤드 높이: 2180 mm; 호스트 ID: 5256435; 치수 - 벽체 opening 면적: 1.89 m2; 체적: 0.108017 m3
기본 벽:A1-32-06A-콘크리트면정리, 시멘트모르타르(미장용), 수성페인트(내부) (18mm):7557741 | 지상 3층 | 3048 | 1600 | 1500 | 새 구성 | 창 | WD842-2단 하부 더블 프로젝트 창(스테인리스 스틸)_1500x1600mm | 7468499 | WD842-2단 하부 더블 프로젝트 창(스테인리스 스틸) | WD842-2단 하부 더블 프로젝트 창(스테인리스 스틸): WD842-2단 하부 더블 프로젝트 창(스테인리스 스틸)_1500x1600mm | 3.60783 | WD842-2단 하부 더블 프로젝트 창(스테인리스 스틸)_1500x1600mm | 2 | 구속조건 - 레벨: 지상 3층; 씰 높이: 1000 mm; 기타 - 창의개폐비: 100; 헤드 높이: 2600 mm; 호스트 ID: 5998918; 치수 - 체적: 0.084837 m3
기본 벽:A1-32-06A-콘크리트면정리, 시멘트모르타르(미장용), 수성페인트(내부) (18mm):7557748 | 지상 3층 | 322.8 | 2620 | 2099.37 | 새 구성 | 벽 | CW112-스테인리스 스틸 커튼월 | 7675291 | 커튼월 | 커튼월: CW112-스테인리스 스틸 커튼월 | 5.50034 | CW112-스테인리스 스틸 커튼월 | 2 | ID 데이터 - 마크: 22; 해설: AW; 구속조건 - 매스와 관련됨: no; 룸 경계: yes; 벽 베이스가 부착됩니다.: no; 상단이 부착됩니다.: no; 베이스 구속조건: 지상 3층; 상단 구속조건: 상위 레벨: 지상 4층; 미연결 높이: 2620 mm; 베이스 간격띄우기: 80 mm; 상단 간격띄우기: -1400 mm; 구조 - 구조: no; 구조적 용도: 비교좌장치; 단면형상 정의 - 단면형상: 수직; 수직 그리드 - 각도: 0 deg; 간격띄우기: 0 mm; 맞춤: 시작; 번호: 4; sets with these values: 2; 치수 - 길이: 2099.37 mm
기본 벽:A1-32-06A-콘크리트면정리, 시멘트모르타르(미장용), 수성페인트(내부) (18mm):7557748 | 지상 3층 | 3048 | 2000 | 1800 | 새 구성 | 창 | WD842-2단 하부 더블 프로젝트 창(스테인리스 스틸)_2000x1800mm | 7468501 | WD842-2단 하부 더블 프로젝트 창(스테인리스 스틸) | WD842-2단 하부 더블 프로젝트 창(스테인리스 스틸): WD842-2단 하부 더블 프로젝트 창(스테인리스 스틸)_2000x1800mm | 5.10973 | WD842-2단 하부 더블 프로젝트 창(스테인리스 스틸)_2000x1800mm | 2 | 구속조건 - 레벨: 지상 3층; 씰 높이: 1000 mm; 기타 - 창의개폐비: 100; 헤드 높이: 2800 mm; 호스트 ID: 2820463; 치수 - 체적: 0.113019 m3
기본 벽:A1-32-06A-콘크리트면정리, 시멘트모르타르(미장용), 수성페인트(내부) (18mm):7557749 | 지상 3층 | 322.8 | 2620 | 2750 | 새 구성 | 벽 | CW112-스테인리스 스틸 커튼월 | 7675291 | 커튼월 | 커튼월: CW112-스테인리스 스틸 커튼월 | 7.205 | CW112-스테인리스 스틸 커튼월 | 2 | ID 데이터 - 마크: 26; 해설: SSD; 구속조건 - 매스와 관련됨: no; 룸 경계: yes; 벽 베이스가 부착됩니다.: no; 상단이 부착됩니다.: no; 베이스 구속조건: 지상 3층; 상단 구속조건: 상위 레벨: 지상 4층; 미연결 높이: 2620 mm; 베이스 간격띄우기: 80 mm; 상단 간격띄우기: -1400 mm; 구조 - 구조: no; 구조적 용도: 비교좌장치; 단면형상 정의 - 단면형상: 수직; 수직 그리드 - 각도: 0 deg; 간격띄우기: 0 mm; 맞춤: 시작; 번호: 4; sets with these values: 2; 치수 - 길이: 2850 mm
기본 벽:A1-32-06A-콘크리트면정리, 시멘트모르타르(미장용), 수성페인트(내부) (18mm):7557768 | 지상 3층 | 322.8 | 6500.03 | 2620 | 새 구성 | 벽 | CW112-스테인리스 스틸 커튼월 | 7675291 | 커튼월 | 커튼월: CW112-스테인리스 스틸 커튼월 | 17.0301 | CW112-스테인리스 스틸 커튼월 | 2 | ID 데이터 - 마크: 27; 해설: SSD; 구속조건 - 매스와 관련됨: no; 룸 경계: yes; 벽 베이스가 부착됩니다.: no; 상단이 부착됩니다.: no; 베이스 구속조건: 지상 3층; 상단 구속조건: 상위 레벨: 지상 4층; 미연결 높이: 2620 mm; 베이스 간격띄우기: 80 mm; 상단 간격띄우기: -1400 mm; 구조 - 구조: no; 구조적 용도: 비교좌장치; 단면형상 정의 - 단면형상: 수직; 수직 그리드 - 각도: 0 deg; 간격띄우기: 0 mm; 맞춤: 시작; 번호: 4; sets with these values: 2; 치수 - 길이: 6500.03 mm
기본 벽:A1-32-06A-콘크리트면정리, 시멘트모르타르(미장용), 수성페인트(내부) (18mm):7557768 | 지상 3층 | 322.8 | 2750 | 2620 | 새 구성 | 벽 | CW112-스테인리스 스틸 커튼월 | 7675291 | 커튼월 | 커튼월: CW112-스테인리스 스틸 커튼월 | 7.205 | CW112-스테인리스 스틸 커튼월 | 2 | ID 데이터 - 마크: 26; 해설: SSD; 구속조건 - 매스와 관련됨: no; 룸 경계: yes; 벽 베이스가 부착됩니다.: no; 상단이 부착됩니다.: no; 베이스 구속조건: 지상 3층; 상단 구속조건: 상위 레벨: 지상 4층; 미연결 높이: 2620 mm; 베이스 간격띄우기: 80 mm; 상단 간격띄우기: -1400 mm; 구조 - 구조: no; 구조적 용도: 비교좌장치; 단면형상 정의 - 단면형상: 수직; 수직 그리드 - 각도: 0 deg; 간격띄우기: 0 mm; 맞춤: 시작; 번호: 4; sets with these values: 2; 치수 - 길이: 2850 mm
기본 벽:A1-32-06A-콘크리트면정리, 시멘트모르타르(미장용), 수성페인트(내부) (18mm):7557768 | 지상 3층 | 322.8 | 6600 | 2620 | 새 구성 | 벽 | CW112-스테인리스 스틸 커튼월 | 7675291 | 커튼월 | 커튼월: CW112-스테인리스 스틸 커튼월 | 17.292 | CW112-스테인리스 스틸 커튼월 | 2 | ID 데이터 - 마크: 26; 해설: SSD; 구속조건 - 매스와 관련됨: no; 룸 경계: yes; 벽 베이스가 부착됩니다.: no; 상단이 부착됩니다.: no; 베이스 구속조건: 지상 3층; 상단 구속조건: 상위 레벨: 지상 4층; 미연결 높이: 2620 mm; 베이스 간격띄우기: 80 mm; 상단 간격띄우기: -1400 mm; 구조 - 구조: no; 구조적 용도: 비교좌장치; 단면형상 정의 - 단면형상: 수직; 수직 그리드 - 각도: 0 deg; 간격띄우기: 0 mm; 맞춤: 시작; 번호: 4; sets with these values: 2; 치수 - 길이: 6600 mm
기본 벽:A1-32-06A-콘크리트면정리, 시멘트모르타르(미장용), 수성페인트(내부) (18mm):7557779 | 지상 3층 | 322.8 |  |  | 새 구성 | 벽 | CW112-스테인리스 스틸 커튼월 | 7675291 | 커튼월 | 커튼월: CW112-스테인리스 스틸 커튼월 | 22.8255 | CW112-스테인리스 스틸 커튼월 | 2 | ID 데이터 - 마크: 28; 해설: SSD; 구속조건 - 매스와 관련됨: no; 룸 경계: yes; 벽 베이스가 부착됩니다.: no; 상단이 부착됩니다.: no; 베이스 구속조건: 지상 3층; 상단 구속조건: 상위 레벨: 지상 4층; 미연결 높이: 2620 mm; 베이스 간격띄우기: 80 mm; 상단 간격띄우기: -1400 mm; 구조 - 구조: no; 구조적 용도: 비교좌장치; 단면형상 정의 - 단면형상: 수직; 수직 그리드 - 각도: 0 deg; 간격띄우기: 0 mm; 맞춤: 시작; 번호: 4; sets with these values: 2; 치수 - 길이: 9900.02 mm; BaseQuantities - Area: 22.8255 m2
기본 벽:A1-32-06A-콘크리트면정리, 시멘트모르타르(미장용), 수성페인트(내부) (18mm):7557779 | 지상 3층 | 3048 | 2100 | 1500 | 새 구성 | 문 | DR121-쌍여닫이문(유리, 일반, 양개) 1500x2100mm | 7693130 | DR121-쌍여닫이문(철재, 일반, 양개) | DR121-쌍여닫이문(철재, 일반, 양개): DR121-쌍여닫이문(유리, 일반, 양개) 1500x2100mm | 3.7857 | DR121-쌍여닫이문(유리, 일반, 양개) 1500x2100mm | 2 | ID 데이터 - 마크: 25WWWWW; 구속조건 - 레벨: 지상 3층; 씰 높이: 55 mm; 기타 - 헤드 높이: 2155 mm; 호스트 ID: 5354050; 치수 - 체적: 0.0603055 m3; 데이터 - 벽체 opening 면적: 3.15 m2
기본 벽:A1-32-06A-콘크리트면정리, 시멘트모르타르(미장용), 수성페인트(내부) (18mm):7557784 | 지상 3층 | 322.8 | 2750 | 2620 | 새 구성 | 벽 | CW112-스테인리스 스틸 커튼월 | 7675291 | 커튼월 | 커튼월: CW112-스테인리스 스틸 커튼월 | 7.205 | CW112-스테인리스 스틸 커튼월 | 2 | ID 데이터 - 마크: 29; 해설: SSD; 구속조건 - 매스와 관련됨: no; 룸 경계: yes; 벽 베이스가 부착됩니다.: no; 상단이 부착됩니다.: no; 베이스 구속조건: 지상 3층; 상단 구속조건: 상위 레벨: 지상 4층; 미연결 높이: 2620 mm; 베이스 간격띄우기: 80 mm; 상단 간격띄우기: -1400 mm; 구조 - 구조: no; 구조적 용도: 비교좌장치; 단면형상 정의 - 단면형상: 수직; 수직 그리드 - 각도: 0 deg; 간격띄우기: 0 mm; 맞춤: 시작; 번호: 4; sets with these values: 2; 치수 - 길이: 2750 mm
기본 벽:A1-32-07A-콘크리트면정리, 바닥방수연장, 시멘트모르타르(미장용), 수성페인트(내부) (24mm):7557818 | 지상 3층 | 3048 | 900 | 2100 | 새 구성 | 문 | DR111-외여닫이문(철재, 일반) 900x2100mm | 7447208 | DR111-외여닫이문(철재, 일반) | DR111-외여닫이문(철재, 일반): DR111-외여닫이문(철재, 일반) 900x2100mm | 3.19384 | DR111-외여닫이문(철재, 일반) 900x2100mm | 2 | 구속조건 - 레벨: 지상 3층; 씰 높이: 80 mm; 기타 - 헤드 높이: 2180 mm; 호스트 ID: 5256435; 치수 - 벽체 opening 면적: 1.89 m2; 체적: 0.108017 m3
기본 벽:A1-32-07A-콘크리트면정리, 바닥방수연장, 시멘트모르타르(미장용), 수성페인트(내부) (24mm):7557823 | 지상 3층 | 3048 | 1000 | 2100 | 새 구성 | 문 | DR111-외여닫이문(철재, 일반)_유리포함 (원형)_2100x1000 | 7452354 | DR111-외여닫이문(철재,일반)_유리포함(원형) | DR111-외여닫이문(철재,일반)_유리포함(원형): DR111-외여닫이문(철재, 일반)_유리포함 (원형)_2100x1000 | 3.71966 | DR111-외여닫이문(철재, 일반)_유리포함 (원형)_2100x1000 | 2 | 구속조건 - 레벨: 지상 3층; 씰 높이: 80 mm; 기타 - 헤드 높이: 2180 mm; 호스트 ID: 2820477; 치수 - 체적: 0.116207 m3
기본 벽:A1-32-07A-콘크리트면정리, 바닥방수연장, 시멘트모르타르(미장용), 수성페인트(내부) (24mm):7557823 | 지상 3층 | 3048 | 600 | 650 | 새 구성 | 문 | DR872-샤프트 점검구(스테인리스 스틸)_650x600 | 3614979 | DR872-샤프트 점검구(스테인리스 스틸) | DR872-샤프트 점검구(스테인리스 스틸): DR872-샤프트 점검구(스테인리스 스틸)_650x600 | 0.851649 | DR872-샤프트 점검구(스테인리스 스틸)_650x600 | 2 | 구속조건 - 레벨: 지상 3층; 씰 높이: 1200 mm; 기타 - 헤드 높이: 1800 mm; 호스트 ID: 2820469; 치수 - 체적: 0.0317935 m3
기본 벽:A1-32-07A-콘크리트면정리, 바닥방수연장, 시멘트모르타르(미장용), 수성페인트(내부) (24mm):7557827 | 지상 3층 | 3048 | 1600 | 650 | 새 구성 | 문 | DR872-샤프트 점검구(스테인리스 스틸)_650x1600 | 3648337 | DR872-샤프트 점검구(스테인리스 스틸) | DR872-샤프트 점검구(스테인리스 스틸): DR872-샤프트 점검구(스테인리스 스틸)_650x1600 | 1.90665 | DR872-샤프트 점검구(스테인리스 스틸)_650x1600 | 2 | 구속조건 - 레벨: 지상 3층; 씰 높이: 80 mm; 기타 - 헤드 높이: 1680 mm; 호스트 ID: 2820465; 치수 - 체적: 0.0736435 m3
2 x 기본 벽:A1-32-07A-콘크리트면정리, 바닥방수연장, 시멘트모르타르(미장용), 수성페인트(내부) (24mm):7557828 | 지상 3층 | 3048 | 2550 | 1100 | 새 구성 | 문 | EE111-엘리베이터문(20인승)_1100x2550 | 7620949 | EE111-엘리베이터문(문) | EE111-엘리베이터문(문): EE111-엘리베이터문(20인승)_1100x2550 | 4.15514 | EE111-엘리베이터문(20인승)_1100x2550 | 2 | 구속조건 - 레벨: 지상 3층; 씰 높이: 80 mm; 기타 - 헤드 높이: 2630 mm; 호스트 ID: 2820445; 치수 - 체적: 0.224818 m3
기본 벽:A1-32-07A-콘크리트면정리, 바닥방수연장, 시멘트모르타르(미장용), 수성페인트(내부) (24mm):7557829 | 지상 3층 | 3048 | 1600 | 650 | 새 구성 | 문 | DR872-샤프트 점검구(스테인리스 스틸)_650x1600 | 3648337 | DR872-샤프트 점검구(스테인리스 스틸) | DR872-샤프트 점검구(스테인리스 스틸): DR872-샤프트 점검구(스테인리스 스틸)_650x1600 | 1.90665 | DR872-샤프트 점검구(스테인리스 스틸)_650x1600 | 2 | 구속조건 - 레벨: 지상 3층; 씰 높이: 80 mm; 기타 - 헤드 높이: 1680 mm; 호스트 ID: 2820443; 치수 - 체적: 0.0736435 m3
기본 벽:A1-32-07A-콘크리트면정리, 바닥방수연장, 시멘트모르타르(미장용), 수성페인트(내부) (24mm):7557829 | 지상 3층 | 3048 | 900 | 2100 | 새 구성 | 문 | DR111-외여닫이문(철재, 일반) 900x2100mm | 7447208 | DR111-외여닫이문(철재, 일반) | DR111-외여닫이문(철재, 일반): DR111-외여닫이문(철재, 일반) 900x2100mm | 3.19384 | DR111-외여닫이문(철재, 일반) 900x2100mm | 2 | 구속조건 - 레벨: 지상 3층; 씰 높이: 80 mm; 기타 - 헤드 높이: 2180 mm; 호스트 ID: 2820443; 치수 - 벽체 opening 면적: 1.89 m2; 체적: 0.108017 m3
기본 벽:A1-32-07A-콘크리트면정리, 바닥방수연장, 시멘트모르타르(미장용), 수성페인트(내부) (24mm):7557829 | 지상 3층 | 3048 | 1100 | 2100 | 새 구성 | 문 | DR111-외여닫이문(철재, 일반) 1100x2100mm 2 | 8088344 | DR111-외여닫이문(철재, 일반) | DR111-외여닫이문(철재, 일반): DR111-외여닫이문(철재, 일반) 1100x2100mm 2 | 3.66584 | DR111-외여닫이문(철재, 일반) 1100x2100mm 2 | 2 | 구속조건 - 레벨: 지상 3층; 씰 높이: 80 mm; 기타 - 헤드 높이: 2180 mm; 호스트 ID: 2820443; 치수 - 벽체 opening 면적: 2.31 m2; 체적: 0.122657 m3
기본 벽:A1-32-06A-콘크리트면정리, 시멘트모르타르(미장용), 수성페인트(내부) (18mm):7561219 | 지상 4층 | 3048 | 1100 | 2100 | 새 구성 | 문 | DR111-외여닫이문(철재, 일반) 1100x2100mm 2 | 8088344 | DR111-외여닫이문(철재, 일반) | DR111-외여닫이문(철재, 일반): DR111-외여닫이문(철재, 일반) 1100x2100mm 2 | 3.66584 | DR111-외여닫이문(철재, 일반) 1100x2100mm 2 | 2 | 구속조건 - 레벨: 지상 4층; 씰 높이: 80 mm; 기타 - 헤드 높이: 2180 mm; 호스트 ID: 2820693; 치수 - 벽체 opening 면적: 2.31 m2; 체적: 0.122657 m3
기본 벽:A1-32-06A-콘크리트면정리, 시멘트모르타르(미장용), 수성페인트(내부) (18mm):7561224 | 지상 4층 | 3048 | 1800 | 2100 | 새 구성 | 문 | DR121-쌍여닫이문(철재, 방화문) 1800x2100mm | 7435628 | DR121-쌍여닫이문(철재, 방화문) | DR121-쌍여닫이문(철재, 방화문): DR121-쌍여닫이문(철재, 방화문) 1800x2100mm | 5.32025 | DR121-쌍여닫이문(철재, 방화문) 1800x2100mm | 2 | 구속조건 - 레벨: 지상 4층; 씰 높이: 80 mm; 기타 - 헤드 높이: 2180 mm; 호스트 ID: 2820717; 치수 - 체적: 0.146498 m3; 데이터 - 벽체 opening 면적: 3.78 m2
기본 벽:A1-32-06A-콘크리트면정리, 시멘트모르타르(미장용), 수성페인트(내부) (18mm):7561227 | 지상 4층 | 3048 | 900 | 2100 | 새 구성 | 문 | DR111-외여닫이문(철재, 일반) 900x2100mm | 7447208 | DR111-외여닫이문(철재, 일반) | DR111-외여닫이문(철재, 일반): DR111-외여닫이문(철재, 일반) 900x2100mm | 3.19384 | DR111-외여닫이문(철재, 일반) 900x2100mm | 2 | 구속조건 - 레벨: 지상 4층; 씰 높이: 80 mm; 기타 - 헤드 높이: 2180 mm; 호스트 ID: 2820693; 치수 - 벽체 opening 면적: 1.89 m2; 체적: 0.108017 m3
기본 벽:A1-32-06A-콘크리트면정리, 시멘트모르타르(미장용), 수성페인트(내부) (18mm):7561228 | 지상 4층 | 3048 | 600 | 800 | 새 구성 | 창 | WD733-그릴창(알루미늄)_600x800mm | 7459609 | WD733-그릴창(알루미늄) | WD733-그릴창(알루미늄): WD733-그릴창(알루미늄)_600x800mm | 2.12048 | WD733-그릴창(알루미늄)_600x800mm | 2 | 구속조건 - 레벨: 지상 4층; 씰 높이: 500 mm; 기타 - 창의개폐비: 50; 헤드 높이: 1300 mm; 호스트 ID: 2820709; 치수 - 체적: 0.0208362 m3
기본 벽:A1-32-06A-콘크리트면정리, 시멘트모르타르(미장용), 수성페인트(내부) (18mm):7561228 | 지상 4층 | 3048 | 800 | 600 | 새 구성 | 창 | WD733-그릴창(알루미늄)_600x800mm | 7459609 | WD733-그릴창(알루미늄) | WD733-그릴창(알루미늄): WD733-그릴창(알루미늄)_600x800mm | 2.12048 | WD733-그릴창(알루미늄)_600x800mm | 2 | 구속조건 - 레벨: 지상 4층; 씰 높이: 500 mm; 기타 - 창의개폐비: 50; 헤드 높이: 1300 mm; 호스트 ID: 2820709; 치수 - 체적: 0.0208362 m3
기본 벽:A1-32-06A-콘크리트면정리, 시멘트모르타르(미장용), 수성페인트(내부) (18mm):7561229 | 지상 4층 | 3048 | 1100 | 2550 | 새 구성 | 문 | EE111-엘리베이터문(13인승)_1100x2550 | 7620945 | EE111-엘리베이터문(문) | EE111-엘리베이터문(문): EE111-엘리베이터문(13인승)_1100x2550 | 4.15514 | EE111-엘리베이터문(13인승)_1100x2550 | 2 | 구속조건 - 레벨: 지상 4층; 씰 높이: 80 mm; 기타 - 헤드 높이: 2630 mm; 호스트 ID: 2820711; 치수 - 체적: 0.224818 m3
기본 벽:A1-32-06A-콘크리트면정리, 시멘트모르타르(미장용), 수성페인트(내부) (18mm):7561234 | 지상 4층 | 3048 | 1600 | 1500 | 새 구성 | 창 | WD842-2단 하부 더블 프로젝트 창(스테인리스 스틸)_1500x1600mm | 7468499 | WD842-2단 하부 더블 프로젝트 창(스테인리스 스틸) | WD842-2단 하부 더블 프로젝트 창(스테인리스 스틸): WD842-2단 하부 더블 프로젝트 창(스테인리스 스틸)_1500x1600mm | 3.60783 | WD842-2단 하부 더블 프로젝트 창(스테인리스 스틸)_1500x1600mm | 2 | 구속조건 - 레벨: 지상 4층; 씰 높이: 1000 mm; 기타 - 창의개폐비: 100; 헤드 높이: 2600 mm; 호스트 ID: 5999125; 치수 - 체적: 0.084837 m3
기본 벽:A1-32-06A-콘크리트면정리, 시멘트모르타르(미장용), 수성페인트(내부) (18mm):7561241 | 지상 4층 | 3048 | 2000 | 1800 | 새 구성 | 창 | WD842-2단 하부 더블 프로젝트 창(스테인리스 스틸)_2000x1800mm | 7468501 | WD842-2단 하부 더블 프로젝트 창(스테인리스 스틸) | WD842-2단 하부 더블 프로젝트 창(스테인리스 스틸): WD842-2단 하부 더블 프로젝트 창(스테인리스 스틸)_2000x1800mm | 5.10973 | WD842-2단 하부 더블 프로젝트 창(스테인리스 스틸)_2000x1800mm | 2 | 구속조건 - 레벨: 지상 4층; 씰 높이: 1000 mm; 기타 - 창의개폐비: 100; 헤드 높이: 2800 mm; 호스트 ID: 2820713; 치수 - 체적: 0.113019 m3
기본 벽:A1-32-06A-콘크리트면정리, 시멘트모르타르(미장용), 수성페인트(내부) (18mm):7561278 | 지상 4층 | 322.8 |  |  | 새 구성 | 벽 | CW112-스테인리스 스틸 커튼월 | 7675291 | 커튼월 | 커튼월: CW112-스테인리스 스틸 커튼월 | 3.93539 | CW112-스테인리스 스틸 커튼월 | 2 | ID 데이터 - 마크: 29; 해설: SSD; 구속조건 - 매스와 관련됨: no; 룸 경계: yes; 벽 베이스가 부착됩니다.: no; 상단이 부착됩니다.: no; 베이스 구속조건: 지상 4층; 상단 구속조건: 상위 레벨: 지상 5층; 미연결 높이: 2620 mm; 베이스 간격띄우기: 80 mm; 상단 간격띄우기: -1400 mm; 구조 - 구조: no; 구조적 용도: 비교좌장치; 단면형상 정의 - 단면형상: 수직; 수직 그리드 - 각도: 0 deg; 간격띄우기: 0 mm; 맞춤: 시작; 번호: 4; sets with these values: 2; 치수 - 길이: 2690.03 mm; BaseQuantities - Area: 3.93539 m2
기본 벽:A1-32-06A-콘크리트면정리, 시멘트모르타르(미장용), 수성페인트(내부) (18mm):7561278 | 지상 4층 | 3048 | 2100 | 1500 | 새 구성 | 문 | DR121-쌍여닫이문(유리, 일반, 양개) 1500x2100mm | 7693130 | DR121-쌍여닫이문(철재, 일반, 양개) | DR121-쌍여닫이문(철재, 일반, 양개): DR121-쌍여닫이문(유리, 일반, 양개) 1500x2100mm | 3.7857 | DR121-쌍여닫이문(유리, 일반, 양개) 1500x2100mm | 2 | ID 데이터 - 마크: 25LLLLL; 구속조건 - 레벨: 지상 4층; 씰 높이: 55 mm; 기타 - 헤드 높이: 2155 mm; 호스트 ID: 5355604; 치수 - 체적: 0.0603055 m3; 데이터 - 벽체 opening 면적: 3.15 m2
기본 벽:A1-32-06A-콘크리트면정리, 시멘트모르타르(미장용), 수성페인트(내부) (18mm):7561286 | 지상 4층 | 3048 | 2000 | 1800 | 새 구성 | 창 | WD842-2단 하부 더블 프로젝트 창(스테인리스 스틸)_2000x1800mm | 7468501 | WD842-2단 하부 더블 프로젝트 창(스테인리스 스틸) | WD842-2단 하부 더블 프로젝트 창(스테인리스 스틸): WD842-2단 하부 더블 프로젝트 창(스테인리스 스틸)_2000x1800mm | 5.10973 | WD842-2단 하부 더블 프로젝트 창(스테인리스 스틸)_2000x1800mm | 2 | 구속조건 - 레벨: 지상 4층; 씰 높이: 1000 mm; 기타 - 창의개폐비: 100; 헤드 높이: 2800 mm; 호스트 ID: 2820733; 치수 - 체적: 0.113019 m3
기본 벽:A1-32-06A-콘크리트면정리, 시멘트모르타르(미장용), 수성페인트(내부) (18mm):7561299 | 지상 4층 | 322.8 |  |  | 새 구성 | 벽 | CW112-스테인리스 스틸 커튼월 | 7675291 | 커튼월 | 커튼월: CW112-스테인리스 스틸 커튼월 | 4.09252 | CW112-스테인리스 스틸 커튼월 | 2 | ID 데이터 - 마크: 29; 해설: SSD; 구속조건 - 매스와 관련됨: no; 룸 경계: yes; 벽 베이스가 부착됩니다.: no; 상단이 부착됩니다.: no; 베이스 구속조건: 지상 4층; 상단 구속조건: 상위 레벨: 지상 5층; 미연결 높이: 2620 mm; 베이스 간격띄우기: 80 mm; 상단 간격띄우기: -1400 mm; 구조 - 구조: no; 구조적 용도: 비교좌장치; 단면형상 정의 - 단면형상: 수직; 수직 그리드 - 각도: 0 deg; 간격띄우기: 0 mm; 맞춤: 시작; 번호: 4; sets with these values: 2; 치수 - 길이: 2750.01 mm; BaseQuantities - Area: 4.09252 m2
기본 벽:A1-32-06A-콘크리트면정리, 시멘트모르타르(미장용), 수성페인트(내부) (18mm):7561299 | 지상 4층 | 3048 | 1500 | 2100 | 새 구성 | 문 | DR121-쌍여닫이문(유리, 일반, 양개) 1500x2100mm | 7693130 | DR121-쌍여닫이문(철재, 일반, 양개) | DR121-쌍여닫이문(철재, 일반, 양개): DR121-쌍여닫이문(유리, 일반, 양개) 1500x2100mm | 3.7857 | DR121-쌍여닫이문(유리, 일반, 양개) 1500x2100mm | 2 | ID 데이터 - 마크: 25MMMMMM; 구속조건 - 레벨: 지상 4층; 씰 높이: 55 mm; 기타 - 헤드 높이: 2155 mm; 호스트 ID: 5355605; 치수 - 체적: 0.0603055 m3; 데이터 - 벽체 opening 면적: 3.15 m2
기본 벽:A1-32-07A-콘크리트면정리, 바닥방수연장, 시멘트모르타르(미장용), 수성페인트(내부) (24mm):7561301 | 지상 4층 | 3048 | 900 | 2100 | 새 구성 | 문 | DR111-외여닫이문(철재, 일반) 900x2100mm | 7447208 | DR111-외여닫이문(철재, 일반) | DR111-외여닫이문(철재, 일반): DR111-외여닫이문(철재, 일반) 900x2100mm | 3.19384 | DR111-외여닫이문(철재, 일반) 900x2100mm | 2 | 구속조건 - 레벨: 지상 4층; 씰 높이: 80 mm; 기타 - 헤드 높이: 2180 mm; 호스트 ID: 2820693; 치수 - 벽체 opening 면적: 1.89 m2; 체적: 0.108017 m3
기본 벽:A1-32-07A-콘크리트면정리, 바닥방수연장, 시멘트모르타르(미장용), 수성페인트(내부) (24mm):7561301 | 지상 4층 | 3048 | 1100 | 2100 | 새 구성 | 문 | DR111-외여닫이문(철재, 일반) 1100x2100mm 2 | 8088344 | DR111-외여닫이문(철재, 일반) | DR111-외여닫이문(철재, 일반): DR111-외여닫이문(철재, 일반) 1100x2100mm 2 | 3.66584 | DR111-외여닫이문(철재, 일반) 1100x2100mm 2 | 2 | 구속조건 - 레벨: 지상 4층; 씰 높이: 80 mm; 기타 - 헤드 높이: 2180 mm; 호스트 ID: 2820693; 치수 - 벽체 opening 면적: 2.31 m2; 체적: 0.122657 m3
기본 벽:A1-32-07A-콘크리트면정리, 바닥방수연장, 시멘트모르타르(미장용), 수성페인트(내부) (24mm):7561301 | 지상 4층 | 3048 | 1600 | 650 | 새 구성 | 문 | DR872-샤프트 점검구(스테인리스 스틸)_650x1600 | 3648337 | DR872-샤프트 점검구(스테인리스 스틸) | DR872-샤프트 점검구(스테인리스 스틸): DR872-샤프트 점검구(스테인리스 스틸)_650x1600 | 1.90665 | DR872-샤프트 점검구(스테인리스 스틸)_650x1600 | 2 | 구속조건 - 레벨: 지상 4층; 씰 높이: 80 mm; 기타 - 헤드 높이: 1680 mm; 호스트 ID: 2820693; 치수 - 체적: 0.0736435 m3
2 x 기본 벽:A1-32-07A-콘크리트면정리, 바닥방수연장, 시멘트모르타르(미장용), 수성페인트(내부) (24mm):7561302 | 지상 4층 | 3048 | 2550 | 1100 | 새 구성 | 문 | EE111-엘리베이터문(20인승)_1100x2550 | 7620949 | EE111-엘리베이터문(문) | EE111-엘리베이터문(문): EE111-엘리베이터문(20인승)_1100x2550 | 4.15514 | EE111-엘리베이터문(20인승)_1100x2550 | 2 | 구속조건 - 레벨: 지상 4층; 씰 높이: 80 mm; 기타 - 헤드 높이: 2630 mm; 호스트 ID: 2820695; 치수 - 체적: 0.224818 m3
기본 벽:A1-32-07A-콘크리트면정리, 바닥방수연장, 시멘트모르타르(미장용), 수성페인트(내부) (24mm):7561303 | 지상 4층 | 3048 | 1600 | 650 | 새 구성 | 문 | DR872-샤프트 점검구(스테인리스 스틸)_650x1600 | 3648337 | DR872-샤프트 점검구(스테인리스 스틸) | DR872-샤프트 점검구(스테인리스 스틸): DR872-샤프트 점검구(스테인리스 스틸)_650x1600 | 1.90665 | DR872-샤프트 점검구(스테인리스 스틸)_650x1600 | 2 | 구속조건 - 레벨: 지상 4층; 씰 높이: 80 mm; 기타 - 헤드 높이: 1680 mm; 호스트 ID: 2820715; 치수 - 체적: 0.0736435 m3
기본 벽:A1-32-07A-콘크리트면정리, 바닥방수연장, 시멘트모르타르(미장용), 수성페인트(내부) (24mm):7561304 | 지상 4층 | 3048 | 1800 | 2100 | 새 구성 | 문 | DR121-쌍여닫이문(철재, 방화문) 1800x2100mm | 7435628 | DR121-쌍여닫이문(철재, 방화문) | DR121-쌍여닫이문(철재, 방화문): DR121-쌍여닫이문(철재, 방화문) 1800x2100mm | 5.32025 | DR121-쌍여닫이문(철재, 방화문) 1800x2100mm | 2 | 구속조건 - 레벨: 지상 4층; 씰 높이: 80 mm; 기타 - 헤드 높이: 2180 mm; 호스트 ID: 2820717; 치수 - 체적: 0.146498 m3; 데이터 - 벽체 opening 면적: 3.78 m2
기본 벽:A1-32-07A-콘크리트면정리, 바닥방수연장, 시멘트모르타르(미장용), 수성페인트(내부) (24mm):7561305 | 지상 4층 | 3048 | 1000 | 2100 | 새 구성 | 문 | DR111-외여닫이문(철재, 일반)_유리포함 (원형)_2100x1000 | 7452354 | DR111-외여닫이문(철재,일반)_유리포함(원형) | DR111-외여닫이문(철재,일반)_유리포함(원형): DR111-외여닫이문(철재, 일반)_유리포함 (원형)_2100x1000 | 3.71966 | DR111-외여닫이문(철재, 일반)_유리포함 (원형)_2100x1000 | 2 | 구속조건 - 레벨: 지상 4층; 씰 높이: 80 mm; 기타 - 헤드 높이: 2180 mm; 호스트 ID: 2820727; 치수 - 체적: 0.116207 m3
기본 벽:A1-32-07A-콘크리트면정리, 바닥방수연장, 시멘트모르타르(미장용), 수성페인트(내부) (24mm):7561305 | 지상 4층 | 3048 | 600 | 650 | 새 구성 | 문 | DR872-샤프트 점검구(스테인리스 스틸)_650x600 | 3614979 | DR872-샤프트 점검구(스테인리스 스틸) | DR872-샤프트 점검구(스테인리스 스틸): DR872-샤프트 점검구(스테인리스 스틸)_650x600 | 0.851649 | DR872-샤프트 점검구(스테인리스 스틸)_650x600 | 2 | 구속조건 - 레벨: 지상 4층; 씰 높이: 1200 mm; 기타 - 헤드 높이: 1800 mm; 호스트 ID: 2820719; 치수 - 체적: 0.0317935 m3
기본 벽:A1-32-07A-콘크리트면정리, 바닥방수연장, 시멘트모르타르(미장용), 수성페인트(내부) (24mm):7561307 | 지상 4층 | 3048 | 2100 | 1000 | 새 구성 | 문 | DR111-외여닫이문(철재, 일반)_유리포함 (원형)_2100x1000 | 7452354 | DR111-외여닫이문(철재,일반)_유리포함(원형) | DR111-외여닫이문(철재,일반)_유리포함(원형): DR111-외여닫이문(철재, 일반)_유리포함 (원형)_2100x1000 | 3.71966 | DR111-외여닫이문(철재, 일반)_유리포함 (원형)_2100x1000 | 2 | 구속조건 - 레벨: 지상 4층; 씰 높이: 80 mm; 기타 - 헤드 높이: 2180 mm; 호스트 ID: 2820697; 치수 - 체적: 0.116207 m3
기본 벽:A1-32-06A-콘크리트면정리, 시멘트모르타르(미장용), 수성페인트(내부) (18mm):7562119:1 | 지상 5층 | 2900 | 5482 | 17.3671 |  |  |  |  |  |  |  | A1-32-06A-콘크리트면정리, 시멘트모르타르(미장용), 수성페인트(내부) (18mm) | 2
기본 벽:A1-32-06A-콘크리트면정리, 시멘트모르타르(미장용), 수성페인트(내부) (18mm):7562124 | 지상 5층 | 3048 | 1800 | 2100 | 새 구성 | 문 | DR121-쌍여닫이문(철재, 방화문) 1800x2100mm | 7435628 | DR121-쌍여닫이문(철재, 방화문) | DR121-쌍여닫이문(철재, 방화문): DR121-쌍여닫이문(철재, 방화문) 1800x2100mm | 5.32025 | DR121-쌍여닫이문(철재, 방화문) 1800x2100mm | 2 | 구속조건 - 레벨: 지상 5층; 씰 높이: 80 mm; 기타 - 헤드 높이: 2180 mm; 호스트 ID: 2821219; 치수 - 체적: 0.146498 m3; 데이터 - 벽체 opening 면적: 3.78 m2
기본 벽:A1-32-06A-콘크리트면정리, 시멘트모르타르(미장용), 수성페인트(내부) (18mm):7562127 | 지상 5층 | 3048 | 900 | 2100 | 새 구성 | 문 | DR111-외여닫이문(철재, 일반) 900x2100mm | 7447208 | DR111-외여닫이문(철재, 일반) | DR111-외여닫이문(철재, 일반): DR111-외여닫이문(철재, 일반) 900x2100mm | 3.19384 | DR111-외여닫이문(철재, 일반) 900x2100mm | 2 | 구속조건 - 레벨: 지상 5층; 씰 높이: 80 mm; 기타 - 헤드 높이: 2180 mm; 호스트 ID: 2821195; 치수 - 벽체 opening 면적: 1.89 m2; 체적: 0.108017 m3
기본 벽:A1-32-06A-콘크리트면정리, 시멘트모르타르(미장용), 수성페인트(내부) (18mm):7562128 | 지상 5층 | 3048 | 600 | 800 | 새 구성 | 창 | WD733-그릴창(알루미늄)_600x800mm | 7459609 | WD733-그릴창(알루미늄) | WD733-그릴창(알루미늄): WD733-그릴창(알루미늄)_600x800mm | 2.12048 | WD733-그릴창(알루미늄)_600x800mm | 2 | 구속조건 - 레벨: 지상 5층; 씰 높이: 500 mm; 기타 - 창의개폐비: 50; 헤드 높이: 1300 mm; 호스트 ID: 2821211; 치수 - 체적: 0.0208362 m3
기본 벽:A1-32-06A-콘크리트면정리, 시멘트모르타르(미장용), 수성페인트(내부) (18mm):7562128 | 지상 5층 | 3048 | 800 | 600 | 새 구성 | 창 | WD733-그릴창(알루미늄)_600x800mm | 7459609 | WD733-그릴창(알루미늄) | WD733-그릴창(알루미늄): WD733-그릴창(알루미늄)_600x800mm | 2.12048 | WD733-그릴창(알루미늄)_600x800mm | 2 | 구속조건 - 레벨: 지상 5층; 씰 높이: 500 mm; 기타 - 창의개폐비: 50; 헤드 높이: 1300 mm; 호스트 ID: 2821211; 치수 - 체적: 0.0208362 m3
기본 벽:A1-32-06A-콘크리트면정리, 시멘트모르타르(미장용), 수성페인트(내부) (18mm):7562129 | 지상 5층 | 3048 | 1100 | 2550 | 새 구성 | 문 | EE111-엘리베이터문(13인승)_1100x2550 | 7620945 | EE111-엘리베이터문(문) | EE111-엘리베이터문(문): EE111-엘리베이터문(13인승)_1100x2550 | 4.15514 | EE111-엘리베이터문(13인승)_1100x2550 | 2 | 구속조건 - 레벨: 지상 5층; 씰 높이: 80 mm; 기타 - 헤드 높이: 2630 mm; 호스트 ID: 2821213; 치수 - 체적: 0.224818 m3
기본 벽:A1-32-06A-콘크리트면정리, 시멘트모르타르(미장용), 수성페인트(내부) (18mm):7562134 | 지상 5층 | 3048 | 1600 | 1500 | 새 구성 | 창 | WD842-2단 하부 더블 프로젝트 창(스테인리스 스틸)_1500x1600mm | 7468499 | WD842-2단 하부 더블 프로젝트 창(스테인리스 스틸) | WD842-2단 하부 더블 프로젝트 창(스테인리스 스틸): WD842-2단 하부 더블 프로젝트 창(스테인리스 스틸)_1500x1600mm | 3.60783 | WD842-2단 하부 더블 프로젝트 창(스테인리스 스틸)_1500x1600mm | 2 | 구속조건 - 레벨: 지상 5층; 씰 높이: 1000 mm; 기타 - 창의개폐비: 100; 헤드 높이: 2600 mm; 호스트 ID: 5999356; 치수 - 체적: 0.084837 m3
기본 벽:A1-32-06A-콘크리트면정리, 시멘트모르타르(미장용), 수성페인트(내부) (18mm):7562141 | 지상 5층 | 3048 | 2000 | 1800 | 새 구성 | 창 | WD842-2단 하부 더블 프로젝트 창(스테인리스 스틸)_2000x1800mm | 7468501 | WD842-2단 하부 더블 프로젝트 창(스테인리스 스틸) | WD842-2단 하부 더블 프로젝트 창(스테인리스 스틸): WD842-2단 하부 더블 프로젝트 창(스테인리스 스틸)_2000x1800mm | 5.10973 | WD842-2단 하부 더블 프로젝트 창(스테인리스 스틸)_2000x1800mm | 2 | 구속조건 - 레벨: 지상 5층; 씰 높이: 1000 mm; 기타 - 창의개폐비: 100; 헤드 높이: 2800 mm; 호스트 ID: 2821215; 치수 - 체적: 0.113019 m3
기본 벽:A1-32-06A-콘크리트면정리, 시멘트모르타르(미장용), 수성페인트(내부) (18mm):7562178 | 지상 5층 | 322.8 |  |  | 새 구성 | 벽 | CW112-스테인리스 스틸 커튼월 | 7675291 | 커튼월 | 커튼월: CW112-스테인리스 스틸 커튼월 | 3.93792 | CW112-스테인리스 스틸 커튼월 | 2 | ID 데이터 - 마크: 29; 해설: SSD; 구속조건 - 매스와 관련됨: no; 룸 경계: yes; 벽 베이스가 부착됩니다.: no; 상단이 부착됩니다.: no; 베이스 구속조건: 지상 5층; 상단 구속조건: 상위 레벨: 지상 6층; 미연결 높이: 2620 mm; 베이스 간격띄우기: 80 mm; 상단 간격띄우기: -1400 mm; 구조 - 구조: no; 구조적 용도: 비교좌장치; 단면형상 정의 - 단면형상: 수직; 수직 그리드 - 각도: 0 deg; 간격띄우기: 0 mm; 맞춤: 시작; 번호: 4; sets with these values: 2; 치수 - 길이: 2700 mm; BaseQuantities - Area: 3.93792 m2
기본 벽:A1-32-06A-콘크리트면정리, 시멘트모르타르(미장용), 수성페인트(내부) (18mm):7562178 | 지상 5층 | 3048 | 2100 | 1500 | 새 구성 | 문 | DR121-쌍여닫이문(유리, 일반, 양개) 1500x2100mm | 7693130 | DR121-쌍여닫이문(철재, 일반, 양개) | DR121-쌍여닫이문(철재, 일반, 양개): DR121-쌍여닫이문(유리, 일반, 양개) 1500x2100mm | 3.7857 | DR121-쌍여닫이문(유리, 일반, 양개) 1500x2100mm | 2 | ID 데이터 - 마크: 25MMMMM; 구속조건 - 레벨: 지상 5층; 씰 높이: 55 mm; 기타 - 헤드 높이: 2155 mm; 호스트 ID: 5355822; 치수 - 체적: 0.0603055 m3; 데이터 - 벽체 opening 면적: 3.15 m2
기본 벽:A1-32-06A-콘크리트면정리, 시멘트모르타르(미장용), 수성페인트(내부) (18mm):7562186 | 지상 5층 | 3048 | 2000 | 1800 | 새 구성 | 창 | WD842-2단 하부 더블 프로젝트 창(스테인리스 스틸)_2000x1800mm | 7468501 | WD842-2단 하부 더블 프로젝트 창(스테인리스 스틸) | WD842-2단 하부 더블 프로젝트 창(스테인리스 스틸): WD842-2단 하부 더블 프로젝트 창(스테인리스 스틸)_2000x1800mm | 5.10973 | WD842-2단 하부 더블 프로젝트 창(스테인리스 스틸)_2000x1800mm | 2 | 구속조건 - 레벨: 지상 5층; 씰 높이: 1000 mm; 기타 - 창의개폐비: 100; 헤드 높이: 2800 mm; 호스트 ID: 2821235; 치수 - 체적: 0.113019 m3
기본 벽:A1-32-07A-콘크리트면정리, 바닥방수연장, 시멘트모르타르(미장용), 수성페인트(내부) (24mm):7562707 | 지상 5층 | 3048 | 900 | 2100 | 새 구성 | 문 | DR111-외여닫이문(철재, 일반) 900x2100mm | 7447208 | DR111-외여닫이문(철재, 일반) | DR111-외여닫이문(철재, 일반): DR111-외여닫이문(철재, 일반) 900x2100mm | 3.19384 | DR111-외여닫이문(철재, 일반) 900x2100mm | 2 | 구속조건 - 레벨: 지상 5층; 씰 높이: 80 mm; 기타 - 헤드 높이: 2180 mm; 호스트 ID: 2821195; 치수 - 벽체 opening 면적: 1.89 m2; 체적: 0.108017 m3
기본 벽:A1-32-07A-콘크리트면정리, 바닥방수연장, 시멘트모르타르(미장용), 수성페인트(내부) (24mm):7562707 | 지상 5층 | 3048 | 1100 | 2100 | 새 구성 | 문 | DR111-외여닫이문(철재, 일반) 1100x2100mm 2 | 8088344 | DR111-외여닫이문(철재, 일반) | DR111-외여닫이문(철재, 일반): DR111-외여닫이문(철재, 일반) 1100x2100mm 2 | 3.66584 | DR111-외여닫이문(철재, 일반) 1100x2100mm 2 | 2 | 구속조건 - 레벨: 지상 5층; 씰 높이: 80 mm; 기타 - 헤드 높이: 2180 mm; 호스트 ID: 2821195; 치수 - 벽체 opening 면적: 2.31 m2; 체적: 0.122657 m3
기본 벽:A1-32-07A-콘크리트면정리, 바닥방수연장, 시멘트모르타르(미장용), 수성페인트(내부) (24mm):7562707 | 지상 5층 | 3048 | 1600 | 650 | 새 구성 | 문 | DR872-샤프트 점검구(스테인리스 스틸)_650x1600 | 3648337 | DR872-샤프트 점검구(스테인리스 스틸) | DR872-샤프트 점검구(스테인리스 스틸): DR872-샤프트 점검구(스테인리스 스틸)_650x1600 | 1.90665 | DR872-샤프트 점검구(스테인리스 스틸)_650x1600 | 2 | 구속조건 - 레벨: 지상 5층; 씰 높이: 80 mm; 기타 - 헤드 높이: 1680 mm; 호스트 ID: 2821195; 치수 - 체적: 0.0736435 m3
2 x 기본 벽:A1-32-07A-콘크리트면정리, 바닥방수연장, 시멘트모르타르(미장용), 수성페인트(내부) (24mm):7562708 | 지상 5층 | 3048 | 2550 | 1100 | 새 구성 | 문 | EE111-엘리베이터문(20인승)_1100x2550 | 7620949 | EE111-엘리베이터문(문) | EE111-엘리베이터문(문): EE111-엘리베이터문(20인승)_1100x2550 | 4.15514 | EE111-엘리베이터문(20인승)_1100x2550 | 2 | 구속조건 - 레벨: 지상 5층; 씰 높이: 80 mm; 기타 - 헤드 높이: 2630 mm; 호스트 ID: 2821197; 치수 - 체적: 0.224818 m3
기본 벽:A1-32-07A-콘크리트면정리, 바닥방수연장, 시멘트모르타르(미장용), 수성페인트(내부) (24mm):7562709 | 지상 5층 | 3048 | 1600 | 650 | 새 구성 | 문 | DR872-샤프트 점검구(스테인리스 스틸)_650x1600 | 3648337 | DR872-샤프트 점검구(스테인리스 스틸) | DR872-샤프트 점검구(스테인리스 스틸): DR872-샤프트 점검구(스테인리스 스틸)_650x1600 | 1.90665 | DR872-샤프트 점검구(스테인리스 스틸)_650x1600 | 2 | 구속조건 - 레벨: 지상 5층; 씰 높이: 80 mm; 기타 - 헤드 높이: 1680 mm; 호스트 ID: 2821217; 치수 - 체적: 0.0736435 m3
기본 벽:A1-32-07A-콘크리트면정리, 바닥방수연장, 시멘트모르타르(미장용), 수성페인트(내부) (24mm):7562710 | 지상 5층 | 3048 | 1800 | 2100 | 새 구성 | 문 | DR121-쌍여닫이문(철재, 방화문) 1800x2100mm | 7435628 | DR121-쌍여닫이문(철재, 방화문) | DR121-쌍여닫이문(철재, 방화문): DR121-쌍여닫이문(철재, 방화문) 1800x2100mm | 5.32025 | DR121-쌍여닫이문(철재, 방화문) 1800x2100mm | 2 | 구속조건 - 레벨: 지상 5층; 씰 높이: 80 mm; 기타 - 헤드 높이: 2180 mm; 호스트 ID: 2821219; 치수 - 체적: 0.146498 m3; 데이터 - 벽체 opening 면적: 3.78 m2
기본 벽:A1-32-07A-콘크리트면정리, 바닥방수연장, 시멘트모르타르(미장용), 수성페인트(내부) (24mm):7562711 | 지상 5층 | 3048 | 1000 | 2100 | 새 구성 | 문 | DR111-외여닫이문(철재, 일반)_유리포함 (원형)_2100x1000 | 7452354 | DR111-외여닫이문(철재,일반)_유리포함(원형) | DR111-외여닫이문(철재,일반)_유리포함(원형): DR111-외여닫이문(철재, 일반)_유리포함 (원형)_2100x1000 | 3.71966 | DR111-외여닫이문(철재, 일반)_유리포함 (원형)_2100x1000 | 2 | 구속조건 - 레벨: 지상 5층; 씰 높이: 80 mm; 기타 - 헤드 높이: 2180 mm; 호스트 ID: 2821229; 치수 - 체적: 0.116207 m3
기본 벽:A1-32-07A-콘크리트면정리, 바닥방수연장, 시멘트모르타르(미장용), 수성페인트(내부) (24mm):7562711 | 지상 5층 | 3048 | 600 | 650 | 새 구성 | 문 | DR872-샤프트 점검구(스테인리스 스틸)_650x600 | 3614979 | DR872-샤프트 점검구(스테인리스 스틸) | DR872-샤프트 점검구(스테인리스 스틸): DR872-샤프트 점검구(스테인리스 스틸)_650x600 | 0.851649 | DR872-샤프트 점검구(스테인리스 스틸)_650x600 | 2 | 구속조건 - 레벨: 지상 5층; 씰 높이: 1200 mm; 기타 - 헤드 높이: 1800 mm; 호스트 ID: 2821221; 치수 - 체적: 0.0317935 m3
기본 벽:A1-32-07A-콘크리트면정리, 바닥방수연장, 시멘트모르타르(미장용), 수성페인트(내부) (24mm):7562713 | 지상 5층 | 3048 | 2100 | 1000 | 새 구성 | 문 | DR111-외여닫이문(철재, 일반)_유리포함 (원형)_2100x1000 | 7452354 | DR111-외여닫이문(철재,일반)_유리포함(원형) | DR111-외여닫이문(철재,일반)_유리포함(원형): DR111-외여닫이문(철재, 일반)_유리포함 (원형)_2100x1000 | 3.71966 | DR111-외여닫이문(철재, 일반)_유리포함 (원형)_2100x1000 | 2 | 구속조건 - 레벨: 지상 5층; 씰 높이: 80 mm; 기타 - 헤드 높이: 2180 mm; 호스트 ID: 2821199; 치수 - 체적: 0.116207 m3
기본 벽:A1-32-06A-콘크리트면정리, 시멘트모르타르(미장용), 수성페인트(내부) (18mm):7563417 | 지상 6층 | 3048 | 1100 | 2100 | 새 구성 | 문 | DR111-외여닫이문(철재, 일반) 1100x2100mm 2 | 8088344 | DR111-외여닫이문(철재, 일반) | DR111-외여닫이문(철재, 일반): DR111-외여닫이문(철재, 일반) 1100x2100mm 2 | 3.66584 | DR111-외여닫이문(철재, 일반) 1100x2100mm 2 | 2 | 구속조건 - 레벨: 지상 6층; 씰 높이: 80 mm; 기타 - 헤드 높이: 2180 mm; 호스트 ID: 2821455; 치수 - 벽체 opening 면적: 2.31 m2; 체적: 0.122657 m3
기본 벽:A1-32-06A-콘크리트면정리, 시멘트모르타르(미장용), 수성페인트(내부) (18mm):7563421 | 지상 6층 | 3048 | 600 | 650 | 새 구성 | 문 | DR872-샤프트 점검구(스테인리스 스틸)_650x600 | 3614979 | DR872-샤프트 점검구(스테인리스 스틸) | DR872-샤프트 점검구(스테인리스 스틸): DR872-샤프트 점검구(스테인리스 스틸)_650x600 | 0.851649 | DR872-샤프트 점검구(스테인리스 스틸)_650x600 | 2 | 구속조건 - 레벨: 지상 6층; 씰 높이: 1200 mm; 기타 - 헤드 높이: 1800 mm; 호스트 ID: 2821481; 치수 - 체적: 0.0317935 m3
기본 벽:A1-32-06A-콘크리트면정리, 시멘트모르타르(미장용), 수성페인트(내부) (18mm):7563421 | 지상 6층 | 3048 | 1000 | 2100 | 새 구성 | 문 | DR111-외여닫이문(철재, 일반)_유리포함 (원형)_2100x1000 | 7452354 | DR111-외여닫이문(철재,일반)_유리포함(원형) | DR111-외여닫이문(철재,일반)_유리포함(원형): DR111-외여닫이문(철재, 일반)_유리포함 (원형)_2100x1000 | 3.71966 | DR111-외여닫이문(철재, 일반)_유리포함 (원형)_2100x1000 | 2 | 구속조건 - 레벨: 지상 6층; 씰 높이: 80 mm; 기타 - 헤드 높이: 2180 mm; 호스트 ID: 2821489; 치수 - 체적: 0.116207 m3
기본 벽:A1-32-06A-콘크리트면정리, 시멘트모르타르(미장용), 수성페인트(내부) (18mm):7563422 | 지상 6층 | 3048 | 1800 | 2100 | 새 구성 | 문 | DR121-쌍여닫이문(철재, 방화문) 1800x2100mm | 7435628 | DR121-쌍여닫이문(철재, 방화문) | DR121-쌍여닫이문(철재, 방화문): DR121-쌍여닫이문(철재, 방화문) 1800x2100mm | 5.32025 | DR121-쌍여닫이문(철재, 방화문) 1800x2100mm | 2 | 구속조건 - 레벨: 지상 6층; 씰 높이: 80 mm; 기타 - 헤드 높이: 2180 mm; 호스트 ID: 2821479; 치수 - 체적: 0.146498 m3; 데이터 - 벽체 opening 면적: 3.78 m2
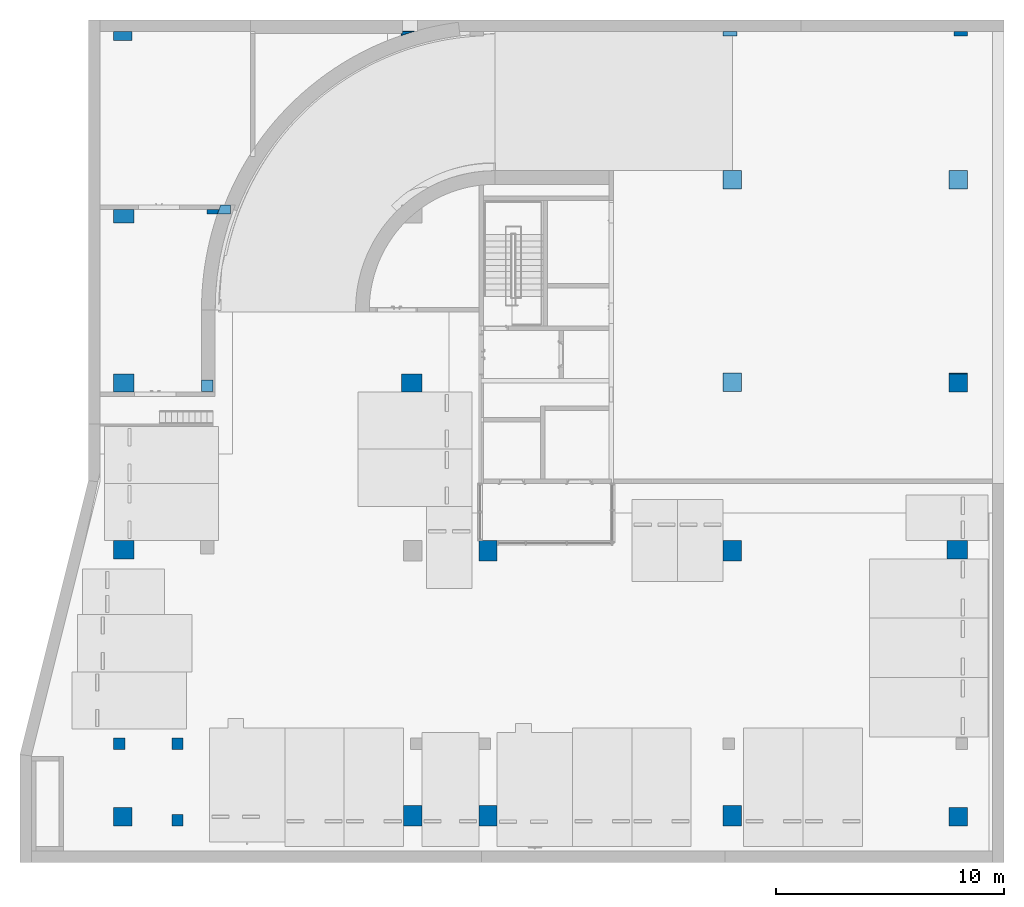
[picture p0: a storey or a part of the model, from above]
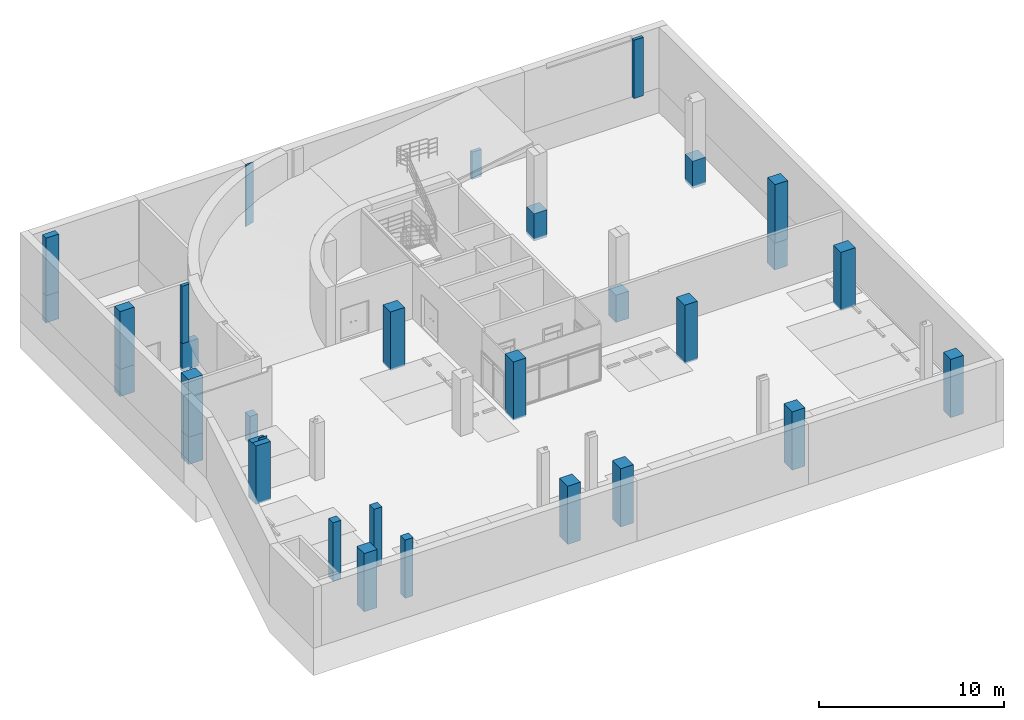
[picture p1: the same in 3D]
Properties of the parts of a building model (IFC2X3), part 27 of 39

# IfcOpeningElement: Opening (863)
Name | In | Depth (mm) | Height (mm) | Width (mm) | 생성 공정 | 카테고리 | 유형 | 유형 ID | 패밀리 | 패밀리 및 유형 | 면적 (m2) | Reference | Pset_OpeningElementCommon, sets with these values
기본 벽:A1-32-06A-콘크리트면정리, 시멘트모르타르(미장용), 수성페인트(내부) (18mm):7563425 | 지상 6층 | 3048 | 900 | 2100 | 새 구성 | 문 | DR111-외여닫이문(철재, 일반) 900x2100mm | 7447208 | DR111-외여닫이문(철재, 일반) | DR111-외여닫이문(철재, 일반): DR111-외여닫이문(철재, 일반) 900x2100mm | 3.19384 | DR111-외여닫이문(철재, 일반) 900x2100mm | 2 | 구속조건 - 레벨: 지상 6층; 씰 높이: 80 mm; 기타 - 헤드 높이: 2180 mm; 호스트 ID: 2821455; 치수 - 벽체 opening 면적: 1.89 m2; 체적: 0.108017 m3
기본 벽:A1-32-06A-콘크리트면정리, 시멘트모르타르(미장용), 수성페인트(내부) (18mm):7563426 | 지상 6층 | 3048 | 600 | 800 | 새 구성 | 창 | WD733-그릴창(알루미늄)_600x800mm | 7459609 | WD733-그릴창(알루미늄) | WD733-그릴창(알루미늄): WD733-그릴창(알루미늄)_600x800mm | 2.12048 | WD733-그릴창(알루미늄)_600x800mm | 2 | 구속조건 - 레벨: 지상 6층; 씰 높이: 500 mm; 기타 - 창의개폐비: 50; 헤드 높이: 1300 mm; 호스트 ID: 2821471; 치수 - 체적: 0.0208362 m3
기본 벽:A1-32-06A-콘크리트면정리, 시멘트모르타르(미장용), 수성페인트(내부) (18mm):7563426 | 지상 6층 | 3048 | 800 | 600 | 새 구성 | 창 | WD733-그릴창(알루미늄)_600x800mm | 7459609 | WD733-그릴창(알루미늄) | WD733-그릴창(알루미늄): WD733-그릴창(알루미늄)_600x800mm | 2.12048 | WD733-그릴창(알루미늄)_600x800mm | 2 | 구속조건 - 레벨: 지상 6층; 씰 높이: 500 mm; 기타 - 창의개폐비: 50; 헤드 높이: 1300 mm; 호스트 ID: 2821471; 치수 - 체적: 0.0208362 m3
기본 벽:A1-32-06A-콘크리트면정리, 시멘트모르타르(미장용), 수성페인트(내부) (18mm):7563427 | 지상 6층 | 3048 | 1100 | 2550 | 새 구성 | 문 | EE111-엘리베이터문(13인승)_1100x2550 | 7620945 | EE111-엘리베이터문(문) | EE111-엘리베이터문(문): EE111-엘리베이터문(13인승)_1100x2550 | 4.15514 | EE111-엘리베이터문(13인승)_1100x2550 | 2 | 구속조건 - 레벨: 지상 6층; 씰 높이: 80 mm; 기타 - 헤드 높이: 2630 mm; 호스트 ID: 2821473; 치수 - 체적: 0.224818 m3
기본 벽:A1-32-06A-콘크리트면정리, 시멘트모르타르(미장용), 수성페인트(내부) (18mm):7563432 | 지상 6층 | 3048 | 1600 | 1500 | 새 구성 | 창 | WD842-2단 하부 더블 프로젝트 창(스테인리스 스틸)_1500x1600mm | 7468499 | WD842-2단 하부 더블 프로젝트 창(스테인리스 스틸) | WD842-2단 하부 더블 프로젝트 창(스테인리스 스틸): WD842-2단 하부 더블 프로젝트 창(스테인리스 스틸)_1500x1600mm | 3.60783 | WD842-2단 하부 더블 프로젝트 창(스테인리스 스틸)_1500x1600mm | 2 | 구속조건 - 레벨: 지상 6층; 씰 높이: 1000 mm; 기타 - 창의개폐비: 100; 헤드 높이: 2600 mm; 호스트 ID: 5999548; 치수 - 체적: 0.084837 m3
기본 벽:A1-32-06A-콘크리트면정리, 시멘트모르타르(미장용), 수성페인트(내부) (18mm):7563439 | 지상 6층 | 3048 | 2000 | 1800 | 새 구성 | 창 | WD842-2단 하부 더블 프로젝트 창(스테인리스 스틸)_2000x1800mm | 7468501 | WD842-2단 하부 더블 프로젝트 창(스테인리스 스틸) | WD842-2단 하부 더블 프로젝트 창(스테인리스 스틸): WD842-2단 하부 더블 프로젝트 창(스테인리스 스틸)_2000x1800mm | 5.10973 | WD842-2단 하부 더블 프로젝트 창(스테인리스 스틸)_2000x1800mm | 2 | 구속조건 - 레벨: 지상 6층; 씰 높이: 1000 mm; 기타 - 창의개폐비: 100; 헤드 높이: 2800 mm; 호스트 ID: 2821475; 치수 - 체적: 0.113019 m3
기본 벽:A1-32-06A-콘크리트면정리, 시멘트모르타르(미장용), 수성페인트(내부) (18mm):7563484 | 지상 6층 | 3048 | 2000 | 1800 | 새 구성 | 창 | WD842-2단 하부 더블 프로젝트 창(스테인리스 스틸)_2000x1800mm | 7468501 | WD842-2단 하부 더블 프로젝트 창(스테인리스 스틸) | WD842-2단 하부 더블 프로젝트 창(스테인리스 스틸): WD842-2단 하부 더블 프로젝트 창(스테인리스 스틸)_2000x1800mm | 5.10973 | WD842-2단 하부 더블 프로젝트 창(스테인리스 스틸)_2000x1800mm | 2 | 구속조건 - 레벨: 지상 6층; 씰 높이: 1000 mm; 기타 - 창의개폐비: 100; 헤드 높이: 2800 mm; 호스트 ID: 2821495; 치수 - 체적: 0.113019 m3
기본 벽:A1-32-06A-콘크리트면정리, 시멘트모르타르(미장용), 수성페인트(내부) (18mm):7563506 | 지상 7층 | 3048 | 1800 | 2100 | 새 구성 | 문 | DR121-쌍여닫이문(철재, 방화문) 1800x2100mm | 7435628 | DR121-쌍여닫이문(철재, 방화문) | DR121-쌍여닫이문(철재, 방화문): DR121-쌍여닫이문(철재, 방화문) 1800x2100mm | 5.32025 | DR121-쌍여닫이문(철재, 방화문) 1800x2100mm | 2 | 구속조건 - 레벨: 지상 7층; 씰 높이: 80 mm; 기타 - 헤드 높이: 2180 mm; 호스트 ID: 2821675; 치수 - 체적: 0.146498 m3; 데이터 - 벽체 opening 면적: 3.78 m2
기본 벽:A1-32-06A-콘크리트면정리, 시멘트모르타르(미장용), 수성페인트(내부) (18mm):7563509:1 | 지상 7층 | 2900 | 2082 | 17.3671 |  |  |  |  |  |  |  | A1-32-06A-콘크리트면정리, 시멘트모르타르(미장용), 수성페인트(내부) (18mm) | 2
기본 벽:A1-32-06A-콘크리트면정리, 시멘트모르타르(미장용), 수성페인트(내부) (18mm):7563510 | 지상 7층 | 3048 | 600 | 800 | 새 구성 | 창 | WD733-그릴창(알루미늄)_600x800mm | 7459609 | WD733-그릴창(알루미늄) | WD733-그릴창(알루미늄): WD733-그릴창(알루미늄)_600x800mm | 2.12048 | WD733-그릴창(알루미늄)_600x800mm | 2 | 구속조건 - 레벨: 지상 7층; 씰 높이: 500 mm; 기타 - 창의개폐비: 50; 헤드 높이: 1300 mm; 호스트 ID: 2821667; 치수 - 체적: 0.0208362 m3
기본 벽:A1-32-06A-콘크리트면정리, 시멘트모르타르(미장용), 수성페인트(내부) (18mm):7563510 | 지상 7층 | 3048 | 800 | 600 | 새 구성 | 창 | WD733-그릴창(알루미늄)_600x800mm | 7459609 | WD733-그릴창(알루미늄) | WD733-그릴창(알루미늄): WD733-그릴창(알루미늄)_600x800mm | 2.12048 | WD733-그릴창(알루미늄)_600x800mm | 2 | 구속조건 - 레벨: 지상 7층; 씰 높이: 500 mm; 기타 - 창의개폐비: 50; 헤드 높이: 1300 mm; 호스트 ID: 2821667; 치수 - 체적: 0.0208362 m3
기본 벽:A1-32-06A-콘크리트면정리, 시멘트모르타르(미장용), 수성페인트(내부) (18mm):7563511 | 지상 7층 | 3048 | 1100 | 2550 | 새 구성 | 문 | EE111-엘리베이터문(13인승)_1100x2550 | 7620945 | EE111-엘리베이터문(문) | EE111-엘리베이터문(문): EE111-엘리베이터문(13인승)_1100x2550 | 4.15514 | EE111-엘리베이터문(13인승)_1100x2550 | 2 | 구속조건 - 레벨: 지상 7층; 씰 높이: 80 mm; 기타 - 헤드 높이: 2630 mm; 호스트 ID: 2821669; 치수 - 체적: 0.224818 m3
기본 벽:A1-32-06A-콘크리트면정리, 시멘트모르타르(미장용), 수성페인트(내부) (18mm):7563516 | 지상 7층 | 3048 | 1600 | 1500 | 새 구성 | 창 | WD842-2단 하부 더블 프로젝트 창(스테인리스 스틸)_1500x1600mm | 7468499 | WD842-2단 하부 더블 프로젝트 창(스테인리스 스틸) | WD842-2단 하부 더블 프로젝트 창(스테인리스 스틸): WD842-2단 하부 더블 프로젝트 창(스테인리스 스틸)_1500x1600mm | 3.60783 | WD842-2단 하부 더블 프로젝트 창(스테인리스 스틸)_1500x1600mm | 2 | 구속조건 - 레벨: 지상 7층; 씰 높이: 1000 mm; 기타 - 창의개폐비: 100; 헤드 높이: 2600 mm; 호스트 ID: 5999768; 치수 - 체적: 0.084837 m3
기본 벽:A1-32-06A-콘크리트면정리, 시멘트모르타르(미장용), 수성페인트(내부) (18mm):7563523 | 지상 7층 | 3048 | 2000 | 1800 | 새 구성 | 창 | WD842-2단 하부 더블 프로젝트 창(스테인리스 스틸)_2000x1800mm | 7468501 | WD842-2단 하부 더블 프로젝트 창(스테인리스 스틸) | WD842-2단 하부 더블 프로젝트 창(스테인리스 스틸): WD842-2단 하부 더블 프로젝트 창(스테인리스 스틸)_2000x1800mm | 5.10973 | WD842-2단 하부 더블 프로젝트 창(스테인리스 스틸)_2000x1800mm | 2 | 구속조건 - 레벨: 지상 7층; 씰 높이: 1000 mm; 기타 - 창의개폐비: 100; 헤드 높이: 2800 mm; 호스트 ID: 2821671; 치수 - 체적: 0.113019 m3
기본 벽:A1-32-06A-콘크리트면정리, 시멘트모르타르(미장용), 수성페인트(내부) (18mm):7563568 | 지상 7층 | 3048 | 2000 | 1800 | 새 구성 | 창 | WD842-2단 하부 더블 프로젝트 창(스테인리스 스틸)_2000x1800mm | 7468501 | WD842-2단 하부 더블 프로젝트 창(스테인리스 스틸) | WD842-2단 하부 더블 프로젝트 창(스테인리스 스틸): WD842-2단 하부 더블 프로젝트 창(스테인리스 스틸)_2000x1800mm | 5.10973 | WD842-2단 하부 더블 프로젝트 창(스테인리스 스틸)_2000x1800mm | 2 | 구속조건 - 레벨: 지상 7층; 씰 높이: 1000 mm; 기타 - 창의개폐비: 100; 헤드 높이: 2800 mm; 호스트 ID: 2821691; 치수 - 체적: 0.113019 m3
기본 벽:A1-32-06A-콘크리트면정리, 시멘트모르타르(미장용), 수성페인트(내부) (18mm):7563585 | 지상 8층 | 3048 | 1100 | 2100 | 새 구성 | 문 | DR111-외여닫이문(철재, 일반) 1100x2100mm 2 | 8088344 | DR111-외여닫이문(철재, 일반) | DR111-외여닫이문(철재, 일반): DR111-외여닫이문(철재, 일반) 1100x2100mm 2 | 3.66584 | DR111-외여닫이문(철재, 일반) 1100x2100mm 2 | 2 | 구속조건 - 레벨: 지상 8층; 씰 높이: 80 mm; 기타 - 헤드 높이: 2180 mm; 호스트 ID: 2821997; 치수 - 벽체 opening 면적: 2.31 m2; 체적: 0.122657 m3
기본 벽:A1-32-06A-콘크리트면정리, 시멘트모르타르(미장용), 수성페인트(내부) (18mm):7563590 | 지상 8층 | 3048 | 1800 | 2100 | 새 구성 | 문 | DR121-쌍여닫이문(철재, 방화문) 1800x2100mm | 7435628 | DR121-쌍여닫이문(철재, 방화문) | DR121-쌍여닫이문(철재, 방화문): DR121-쌍여닫이문(철재, 방화문) 1800x2100mm | 5.32025 | DR121-쌍여닫이문(철재, 방화문) 1800x2100mm | 2 | 구속조건 - 레벨: 지상 8층; 씰 높이: 80 mm; 기타 - 헤드 높이: 2180 mm; 호스트 ID: 2822021; 치수 - 체적: 0.146498 m3; 데이터 - 벽체 opening 면적: 3.78 m2
기본 벽:A1-32-06A-콘크리트면정리, 시멘트모르타르(미장용), 수성페인트(내부) (18mm):7563593 | 지상 8층 | 3048 | 900 | 2100 | 새 구성 | 문 | DR111-외여닫이문(철재, 일반) 900x2100mm | 7447208 | DR111-외여닫이문(철재, 일반) | DR111-외여닫이문(철재, 일반): DR111-외여닫이문(철재, 일반) 900x2100mm | 3.19384 | DR111-외여닫이문(철재, 일반) 900x2100mm | 2 | 구속조건 - 레벨: 지상 8층; 씰 높이: 80 mm; 기타 - 헤드 높이: 2180 mm; 호스트 ID: 2821997; 치수 - 벽체 opening 면적: 1.89 m2; 체적: 0.108017 m3
기본 벽:A1-32-06A-콘크리트면정리, 시멘트모르타르(미장용), 수성페인트(내부) (18mm):7563595 | 지상 8층 | 3048 | 1100 | 2550 | 새 구성 | 문 | EE111-엘리베이터문(13인승)_1100x2550 | 7620945 | EE111-엘리베이터문(문) | EE111-엘리베이터문(문): EE111-엘리베이터문(13인승)_1100x2550 | 4.15514 | EE111-엘리베이터문(13인승)_1100x2550 | 2 | 구속조건 - 레벨: 지상 8층; 씰 높이: 80 mm; 기타 - 헤드 높이: 2630 mm; 호스트 ID: 2822015; 치수 - 체적: 0.224818 m3
기본 벽:A1-32-06A-콘크리트면정리, 시멘트모르타르(미장용), 수성페인트(내부) (18mm):7563600 | 지상 8층 | 3048 | 1600 | 1500 | 새 구성 | 창 | WD842-2단 하부 더블 프로젝트 창(스테인리스 스틸)_1500x1600mm | 7468499 | WD842-2단 하부 더블 프로젝트 창(스테인리스 스틸) | WD842-2단 하부 더블 프로젝트 창(스테인리스 스틸): WD842-2단 하부 더블 프로젝트 창(스테인리스 스틸)_1500x1600mm | 3.60783 | WD842-2단 하부 더블 프로젝트 창(스테인리스 스틸)_1500x1600mm | 2 | 구속조건 - 레벨: 지상 8층; 씰 높이: 1000 mm; 기타 - 창의개폐비: 100; 헤드 높이: 2600 mm; 호스트 ID: 5999969; 치수 - 체적: 0.084837 m3
기본 벽:A1-32-06A-콘크리트면정리, 시멘트모르타르(미장용), 수성페인트(내부) (18mm):7563607 | 지상 8층 | 3048 | 2000 | 1800 | 새 구성 | 창 | WD842-2단 하부 더블 프로젝트 창(스테인리스 스틸)_2000x1800mm | 7468501 | WD842-2단 하부 더블 프로젝트 창(스테인리스 스틸) | WD842-2단 하부 더블 프로젝트 창(스테인리스 스틸): WD842-2단 하부 더블 프로젝트 창(스테인리스 스틸)_2000x1800mm | 5.10973 | WD842-2단 하부 더블 프로젝트 창(스테인리스 스틸)_2000x1800mm | 2 | 구속조건 - 레벨: 지상 8층; 씰 높이: 1000 mm; 기타 - 창의개폐비: 100; 헤드 높이: 2800 mm; 호스트 ID: 2822017; 치수 - 체적: 0.113019 m3
기본 벽:A1-32-06A-콘크리트면정리, 시멘트모르타르(미장용), 수성페인트(내부) (18mm):7563652 | 지상 8층 | 3048 | 2000 | 1800 | 새 구성 | 창 | WD842-2단 하부 더블 프로젝트 창(스테인리스 스틸)_2000x1800mm | 7468501 | WD842-2단 하부 더블 프로젝트 창(스테인리스 스틸) | WD842-2단 하부 더블 프로젝트 창(스테인리스 스틸): WD842-2단 하부 더블 프로젝트 창(스테인리스 스틸)_2000x1800mm | 5.10973 | WD842-2단 하부 더블 프로젝트 창(스테인리스 스틸)_2000x1800mm | 2 | 구속조건 - 레벨: 지상 8층; 씰 높이: 1000 mm; 기타 - 창의개폐비: 100; 헤드 높이: 2800 mm; 호스트 ID: 2822037; 치수 - 체적: 0.113019 m3
기본 벽:A1-32-07A-콘크리트면정리, 바닥방수연장, 시멘트모르타르(미장용), 수성페인트(내부) (24mm):7563884 | 지상 6층 | 3048 | 900 | 2100 | 새 구성 | 문 | DR111-외여닫이문(철재, 일반) 900x2100mm | 7447208 | DR111-외여닫이문(철재, 일반) | DR111-외여닫이문(철재, 일반): DR111-외여닫이문(철재, 일반) 900x2100mm | 3.19384 | DR111-외여닫이문(철재, 일반) 900x2100mm | 2 | 구속조건 - 레벨: 지상 6층; 씰 높이: 80 mm; 기타 - 헤드 높이: 2180 mm; 호스트 ID: 2821455; 치수 - 벽체 opening 면적: 1.89 m2; 체적: 0.108017 m3
기본 벽:A1-32-07A-콘크리트면정리, 바닥방수연장, 시멘트모르타르(미장용), 수성페인트(내부) (24mm):7563884 | 지상 6층 | 3048 | 1100 | 2100 | 새 구성 | 문 | DR111-외여닫이문(철재, 일반) 1100x2100mm 2 | 8088344 | DR111-외여닫이문(철재, 일반) | DR111-외여닫이문(철재, 일반): DR111-외여닫이문(철재, 일반) 1100x2100mm 2 | 3.66584 | DR111-외여닫이문(철재, 일반) 1100x2100mm 2 | 2 | 구속조건 - 레벨: 지상 6층; 씰 높이: 80 mm; 기타 - 헤드 높이: 2180 mm; 호스트 ID: 2821455; 치수 - 벽체 opening 면적: 2.31 m2; 체적: 0.122657 m3
기본 벽:A1-32-07A-콘크리트면정리, 바닥방수연장, 시멘트모르타르(미장용), 수성페인트(내부) (24mm):7563884 | 지상 6층 | 3048 | 1600 | 650 | 새 구성 | 문 | DR872-샤프트 점검구(스테인리스 스틸)_650x1600 | 3648337 | DR872-샤프트 점검구(스테인리스 스틸) | DR872-샤프트 점검구(스테인리스 스틸): DR872-샤프트 점검구(스테인리스 스틸)_650x1600 | 1.90665 | DR872-샤프트 점검구(스테인리스 스틸)_650x1600 | 2 | 구속조건 - 레벨: 지상 6층; 씰 높이: 80 mm; 기타 - 헤드 높이: 1680 mm; 호스트 ID: 2821455; 치수 - 체적: 0.0736435 m3
2 x 기본 벽:A1-32-07A-콘크리트면정리, 바닥방수연장, 시멘트모르타르(미장용), 수성페인트(내부) (24mm):7563885 | 지상 6층 | 3048 | 2550 | 1100 | 새 구성 | 문 | EE111-엘리베이터문(20인승)_1100x2550 | 7620949 | EE111-엘리베이터문(문) | EE111-엘리베이터문(문): EE111-엘리베이터문(20인승)_1100x2550 | 4.15514 | EE111-엘리베이터문(20인승)_1100x2550 | 2 | 구속조건 - 레벨: 지상 6층; 씰 높이: 80 mm; 기타 - 헤드 높이: 2630 mm; 호스트 ID: 2821457; 치수 - 체적: 0.224818 m3
기본 벽:A1-32-07A-콘크리트면정리, 바닥방수연장, 시멘트모르타르(미장용), 수성페인트(내부) (24mm):7563886 | 지상 6층 | 3048 | 1600 | 650 | 새 구성 | 문 | DR872-샤프트 점검구(스테인리스 스틸)_650x1600 | 3648337 | DR872-샤프트 점검구(스테인리스 스틸) | DR872-샤프트 점검구(스테인리스 스틸): DR872-샤프트 점검구(스테인리스 스틸)_650x1600 | 1.90665 | DR872-샤프트 점검구(스테인리스 스틸)_650x1600 | 2 | 구속조건 - 레벨: 지상 6층; 씰 높이: 80 mm; 기타 - 헤드 높이: 1680 mm; 호스트 ID: 2821477; 치수 - 체적: 0.0736435 m3
기본 벽:A1-32-07A-콘크리트면정리, 바닥방수연장, 시멘트모르타르(미장용), 수성페인트(내부) (24mm):7563887 | 지상 6층 | 3048 | 1800 | 2100 | 새 구성 | 문 | DR121-쌍여닫이문(철재, 방화문) 1800x2100mm | 7435628 | DR121-쌍여닫이문(철재, 방화문) | DR121-쌍여닫이문(철재, 방화문): DR121-쌍여닫이문(철재, 방화문) 1800x2100mm | 5.32025 | DR121-쌍여닫이문(철재, 방화문) 1800x2100mm | 2 | 구속조건 - 레벨: 지상 6층; 씰 높이: 80 mm; 기타 - 헤드 높이: 2180 mm; 호스트 ID: 2821479; 치수 - 체적: 0.146498 m3; 데이터 - 벽체 opening 면적: 3.78 m2
기본 벽:A1-32-07A-콘크리트면정리, 바닥방수연장, 시멘트모르타르(미장용), 수성페인트(내부) (24mm):7563888 | 지상 6층 | 3048 | 600 | 650 | 새 구성 | 문 | DR872-샤프트 점검구(스테인리스 스틸)_650x600 | 3614979 | DR872-샤프트 점검구(스테인리스 스틸) | DR872-샤프트 점검구(스테인리스 스틸): DR872-샤프트 점검구(스테인리스 스틸)_650x600 | 0.851649 | DR872-샤프트 점검구(스테인리스 스틸)_650x600 | 2 | 구속조건 - 레벨: 지상 6층; 씰 높이: 1200 mm; 기타 - 헤드 높이: 1800 mm; 호스트 ID: 2821481; 치수 - 체적: 0.0317935 m3
기본 벽:A1-32-07A-콘크리트면정리, 바닥방수연장, 시멘트모르타르(미장용), 수성페인트(내부) (24mm):7563888 | 지상 6층 | 3048 | 1000 | 2100 | 새 구성 | 문 | DR111-외여닫이문(철재, 일반)_유리포함 (원형)_2100x1000 | 7452354 | DR111-외여닫이문(철재,일반)_유리포함(원형) | DR111-외여닫이문(철재,일반)_유리포함(원형): DR111-외여닫이문(철재, 일반)_유리포함 (원형)_2100x1000 | 3.71966 | DR111-외여닫이문(철재, 일반)_유리포함 (원형)_2100x1000 | 2 | 구속조건 - 레벨: 지상 6층; 씰 높이: 80 mm; 기타 - 헤드 높이: 2180 mm; 호스트 ID: 2821489; 치수 - 체적: 0.116207 m3
기본 벽:A1-32-07A-콘크리트면정리, 바닥방수연장, 시멘트모르타르(미장용), 수성페인트(내부) (24mm):7563890 | 지상 6층 | 3048 | 2100 | 1000 | 새 구성 | 문 | DR111-외여닫이문(철재, 일반)_유리포함 (원형)_2100x1000 | 7452354 | DR111-외여닫이문(철재,일반)_유리포함(원형) | DR111-외여닫이문(철재,일반)_유리포함(원형): DR111-외여닫이문(철재, 일반)_유리포함 (원형)_2100x1000 | 3.71966 | DR111-외여닫이문(철재, 일반)_유리포함 (원형)_2100x1000 | 2 | 구속조건 - 레벨: 지상 6층; 씰 높이: 80 mm; 기타 - 헤드 높이: 2180 mm; 호스트 ID: 2821459; 치수 - 체적: 0.116207 m3
기본 벽:A1-32-07A-콘크리트면정리, 바닥방수연장, 시멘트모르타르(미장용), 수성페인트(내부) (24mm):7563897 | 지상 7층 | 3048 | 900 | 2100 | 새 구성 | 문 | DR111-외여닫이문(철재, 일반) 900x2100mm | 7447208 | DR111-외여닫이문(철재, 일반) | DR111-외여닫이문(철재, 일반): DR111-외여닫이문(철재, 일반) 900x2100mm | 3.19384 | DR111-외여닫이문(철재, 일반) 900x2100mm | 2 | 구속조건 - 레벨: 지상 7층; 씰 높이: 80 mm; 기타 - 헤드 높이: 2180 mm; 호스트 ID: 2821651; 치수 - 벽체 opening 면적: 1.89 m2; 체적: 0.108017 m3
기본 벽:A1-32-07A-콘크리트면정리, 바닥방수연장, 시멘트모르타르(미장용), 수성페인트(내부) (24mm):7563897 | 지상 7층 | 3048 | 1100 | 2100 | 새 구성 | 문 | DR111-외여닫이문(철재, 일반) 1100x2100mm 2 | 8088344 | DR111-외여닫이문(철재, 일반) | DR111-외여닫이문(철재, 일반): DR111-외여닫이문(철재, 일반) 1100x2100mm 2 | 3.66584 | DR111-외여닫이문(철재, 일반) 1100x2100mm 2 | 2 | 구속조건 - 레벨: 지상 7층; 씰 높이: 80 mm; 기타 - 헤드 높이: 2180 mm; 호스트 ID: 2821651; 치수 - 벽체 opening 면적: 2.31 m2; 체적: 0.122657 m3
기본 벽:A1-32-07A-콘크리트면정리, 바닥방수연장, 시멘트모르타르(미장용), 수성페인트(내부) (24mm):7563897 | 지상 7층 | 3048 | 1600 | 650 | 새 구성 | 문 | DR872-샤프트 점검구(스테인리스 스틸)_650x1600 | 3648337 | DR872-샤프트 점검구(스테인리스 스틸) | DR872-샤프트 점검구(스테인리스 스틸): DR872-샤프트 점검구(스테인리스 스틸)_650x1600 | 1.90665 | DR872-샤프트 점검구(스테인리스 스틸)_650x1600 | 2 | 구속조건 - 레벨: 지상 7층; 씰 높이: 80 mm; 기타 - 헤드 높이: 1680 mm; 호스트 ID: 2821651; 치수 - 체적: 0.0736435 m3
2 x 기본 벽:A1-32-07A-콘크리트면정리, 바닥방수연장, 시멘트모르타르(미장용), 수성페인트(내부) (24mm):7563898 | 지상 7층 | 3048 | 2550 | 1100 | 새 구성 | 문 | EE111-엘리베이터문(20인승)_1100x2550 | 7620949 | EE111-엘리베이터문(문) | EE111-엘리베이터문(문): EE111-엘리베이터문(20인승)_1100x2550 | 4.15514 | EE111-엘리베이터문(20인승)_1100x2550 | 2 | 구속조건 - 레벨: 지상 7층; 씰 높이: 80 mm; 기타 - 헤드 높이: 2630 mm; 호스트 ID: 2821653; 치수 - 체적: 0.224818 m3
기본 벽:A1-32-07A-콘크리트면정리, 바닥방수연장, 시멘트모르타르(미장용), 수성페인트(내부) (24mm):7563900 | 지상 7층 | 3048 | 1800 | 2100 | 새 구성 | 문 | DR121-쌍여닫이문(철재, 방화문) 1800x2100mm | 7435628 | DR121-쌍여닫이문(철재, 방화문) | DR121-쌍여닫이문(철재, 방화문): DR121-쌍여닫이문(철재, 방화문) 1800x2100mm | 5.32025 | DR121-쌍여닫이문(철재, 방화문) 1800x2100mm | 2 | 구속조건 - 레벨: 지상 7층; 씰 높이: 80 mm; 기타 - 헤드 높이: 2180 mm; 호스트 ID: 2821675; 치수 - 체적: 0.146498 m3; 데이터 - 벽체 opening 면적: 3.78 m2
기본 벽:A1-32-07A-콘크리트면정리, 바닥방수연장, 시멘트모르타르(미장용), 수성페인트(내부) (24mm):7563901 | 지상 7층 | 3048 | 1000 | 2100 | 새 구성 | 문 | DR111-외여닫이문(철재, 일반)_유리포함 (원형)_2100x1000 | 7452354 | DR111-외여닫이문(철재,일반)_유리포함(원형) | DR111-외여닫이문(철재,일반)_유리포함(원형): DR111-외여닫이문(철재, 일반)_유리포함 (원형)_2100x1000 | 3.71966 | DR111-외여닫이문(철재, 일반)_유리포함 (원형)_2100x1000 | 2 | 구속조건 - 레벨: 지상 7층; 씰 높이: 80 mm; 기타 - 헤드 높이: 2180 mm; 호스트 ID: 2821685; 치수 - 체적: 0.116207 m3
기본 벽:A1-32-07A-콘크리트면정리, 바닥방수연장, 시멘트모르타르(미장용), 수성페인트(내부) (24mm):7563901 | 지상 7층 | 3048 | 600 | 650 | 새 구성 | 문 | DR872-샤프트 점검구(스테인리스 스틸)_650x600 | 3614979 | DR872-샤프트 점검구(스테인리스 스틸) | DR872-샤프트 점검구(스테인리스 스틸): DR872-샤프트 점검구(스테인리스 스틸)_650x600 | 0.851649 | DR872-샤프트 점검구(스테인리스 스틸)_650x600 | 2 | 구속조건 - 레벨: 지상 7층; 씰 높이: 1200 mm; 기타 - 헤드 높이: 1800 mm; 호스트 ID: 2821677; 치수 - 체적: 0.0317935 m3
기본 벽:A1-32-07A-콘크리트면정리, 바닥방수연장, 시멘트모르타르(미장용), 수성페인트(내부) (24mm):7563903 | 지상 7층 | 3048 | 2100 | 1000 | 새 구성 | 문 | DR111-외여닫이문(철재, 일반)_유리포함 (원형)_2100x1000 | 7452354 | DR111-외여닫이문(철재,일반)_유리포함(원형) | DR111-외여닫이문(철재,일반)_유리포함(원형): DR111-외여닫이문(철재, 일반)_유리포함 (원형)_2100x1000 | 3.71966 | DR111-외여닫이문(철재, 일반)_유리포함 (원형)_2100x1000 | 2 | 구속조건 - 레벨: 지상 7층; 씰 높이: 80 mm; 기타 - 헤드 높이: 2180 mm; 호스트 ID: 2821655; 치수 - 체적: 0.116207 m3
기본 벽:A1-32-07A-콘크리트면정리, 바닥방수연장, 시멘트모르타르(미장용), 수성페인트(내부) (24mm):7563910 | 지상 8층 | 3048 | 900 | 2100 | 새 구성 | 문 | DR111-외여닫이문(철재, 일반) 900x2100mm | 7447208 | DR111-외여닫이문(철재, 일반) | DR111-외여닫이문(철재, 일반): DR111-외여닫이문(철재, 일반) 900x2100mm | 3.19384 | DR111-외여닫이문(철재, 일반) 900x2100mm | 2 | 구속조건 - 레벨: 지상 8층; 씰 높이: 80 mm; 기타 - 헤드 높이: 2180 mm; 호스트 ID: 2821997; 치수 - 벽체 opening 면적: 1.89 m2; 체적: 0.108017 m3
기본 벽:A1-32-07A-콘크리트면정리, 바닥방수연장, 시멘트모르타르(미장용), 수성페인트(내부) (24mm):7563910 | 지상 8층 | 3048 | 1100 | 2100 | 새 구성 | 문 | DR111-외여닫이문(철재, 일반) 1100x2100mm 2 | 8088344 | DR111-외여닫이문(철재, 일반) | DR111-외여닫이문(철재, 일반): DR111-외여닫이문(철재, 일반) 1100x2100mm 2 | 3.66584 | DR111-외여닫이문(철재, 일반) 1100x2100mm 2 | 2 | 구속조건 - 레벨: 지상 8층; 씰 높이: 80 mm; 기타 - 헤드 높이: 2180 mm; 호스트 ID: 2821997; 치수 - 벽체 opening 면적: 2.31 m2; 체적: 0.122657 m3
기본 벽:A1-32-07A-콘크리트면정리, 바닥방수연장, 시멘트모르타르(미장용), 수성페인트(내부) (24mm):7563910 | 지상 8층 | 3048 | 1600 | 650 | 새 구성 | 문 | DR872-샤프트 점검구(스테인리스 스틸)_650x1600 | 3648337 | DR872-샤프트 점검구(스테인리스 스틸) | DR872-샤프트 점검구(스테인리스 스틸): DR872-샤프트 점검구(스테인리스 스틸)_650x1600 | 1.90665 | DR872-샤프트 점검구(스테인리스 스틸)_650x1600 | 2 | 구속조건 - 레벨: 지상 8층; 씰 높이: 80 mm; 기타 - 헤드 높이: 1680 mm; 호스트 ID: 2821997; 치수 - 체적: 0.0736435 m3
2 x 기본 벽:A1-32-07A-콘크리트면정리, 바닥방수연장, 시멘트모르타르(미장용), 수성페인트(내부) (24mm):7563911 | 지상 8층 | 3048 | 2550 | 1100 | 새 구성 | 문 | EE111-엘리베이터문(20인승)_1100x2550 | 7620949 | EE111-엘리베이터문(문) | EE111-엘리베이터문(문): EE111-엘리베이터문(20인승)_1100x2550 | 4.15514 | EE111-엘리베이터문(20인승)_1100x2550 | 2 | 구속조건 - 레벨: 지상 8층; 씰 높이: 80 mm; 기타 - 헤드 높이: 2630 mm; 호스트 ID: 2821999; 치수 - 체적: 0.224818 m3
기본 벽:A1-32-07A-콘크리트면정리, 바닥방수연장, 시멘트모르타르(미장용), 수성페인트(내부) (24mm):7563913 | 지상 8층 | 3048 | 1800 | 2100 | 새 구성 | 문 | DR121-쌍여닫이문(철재, 방화문) 1800x2100mm | 7435628 | DR121-쌍여닫이문(철재, 방화문) | DR121-쌍여닫이문(철재, 방화문): DR121-쌍여닫이문(철재, 방화문) 1800x2100mm | 5.32025 | DR121-쌍여닫이문(철재, 방화문) 1800x2100mm | 2 | 구속조건 - 레벨: 지상 8층; 씰 높이: 80 mm; 기타 - 헤드 높이: 2180 mm; 호스트 ID: 2822021; 치수 - 체적: 0.146498 m3; 데이터 - 벽체 opening 면적: 3.78 m2
기본 벽:A1-32-07A-콘크리트면정리, 바닥방수연장, 시멘트모르타르(미장용), 수성페인트(내부) (24mm):7563914 | 지상 8층 | 3048 | 1000 | 2100 | 새 구성 | 문 | DR111-외여닫이문(철재, 일반)_유리포함 (원형)_2100x1000 | 7452354 | DR111-외여닫이문(철재,일반)_유리포함(원형) | DR111-외여닫이문(철재,일반)_유리포함(원형): DR111-외여닫이문(철재, 일반)_유리포함 (원형)_2100x1000 | 3.71966 | DR111-외여닫이문(철재, 일반)_유리포함 (원형)_2100x1000 | 2 | 구속조건 - 레벨: 지상 8층; 씰 높이: 80 mm; 기타 - 헤드 높이: 2180 mm; 호스트 ID: 2822031; 치수 - 체적: 0.116207 m3
기본 벽:A1-32-07A-콘크리트면정리, 바닥방수연장, 시멘트모르타르(미장용), 수성페인트(내부) (24mm):7563916 | 지상 8층 | 3048 | 1000 | 2100 | 새 구성 | 문 | DR111-외여닫이문(철재, 일반)_유리포함 (원형)_2100x1000 | 7452354 | DR111-외여닫이문(철재,일반)_유리포함(원형) | DR111-외여닫이문(철재,일반)_유리포함(원형): DR111-외여닫이문(철재, 일반)_유리포함 (원형)_2100x1000 | 3.71966 | DR111-외여닫이문(철재, 일반)_유리포함 (원형)_2100x1000 | 2 | 구속조건 - 레벨: 지상 8층; 씰 높이: 80 mm; 기타 - 헤드 높이: 2180 mm; 호스트 ID: 2822001; 치수 - 체적: 0.116207 m3
기본 벽:A1-32-07A-콘크리트면정리, 바닥방수연장, 시멘트모르타르(미장용), 수성페인트(내부) (24mm):7563923 | 지상 9층 | 3048 | 900 | 2100 | 새 구성 | 문 | DR111-외여닫이문(철재, 일반) 900x2100mm | 7447208 | DR111-외여닫이문(철재, 일반) | DR111-외여닫이문(철재, 일반): DR111-외여닫이문(철재, 일반) 900x2100mm | 3.19384 | DR111-외여닫이문(철재, 일반) 900x2100mm | 2 | 구속조건 - 레벨: 지상 9층; 씰 높이: 80 mm; 기타 - 헤드 높이: 2180 mm; 호스트 ID: 2822203; 치수 - 벽체 opening 면적: 1.89 m2; 체적: 0.108017 m3
기본 벽:A1-32-07A-콘크리트면정리, 바닥방수연장, 시멘트모르타르(미장용), 수성페인트(내부) (24mm):7563923 | 지상 9층 | 3048 | 1100 | 2100 | 새 구성 | 문 | DR111-외여닫이문(철재, 일반) 1100x2100mm 2 | 8088344 | DR111-외여닫이문(철재, 일반) | DR111-외여닫이문(철재, 일반): DR111-외여닫이문(철재, 일반) 1100x2100mm 2 | 3.66584 | DR111-외여닫이문(철재, 일반) 1100x2100mm 2 | 2 | 구속조건 - 레벨: 지상 9층; 씰 높이: 80 mm; 기타 - 헤드 높이: 2180 mm; 호스트 ID: 2822203; 치수 - 벽체 opening 면적: 2.31 m2; 체적: 0.122657 m3
기본 벽:A1-32-07A-콘크리트면정리, 바닥방수연장, 시멘트모르타르(미장용), 수성페인트(내부) (24mm):7563923 | 지상 9층 | 3048 | 1600 | 650 | 새 구성 | 문 | DR872-샤프트 점검구(스테인리스 스틸)_650x1600 | 3648337 | DR872-샤프트 점검구(스테인리스 스틸) | DR872-샤프트 점검구(스테인리스 스틸): DR872-샤프트 점검구(스테인리스 스틸)_650x1600 | 1.90665 | DR872-샤프트 점검구(스테인리스 스틸)_650x1600 | 2 | 구속조건 - 레벨: 지상 9층; 씰 높이: 80 mm; 기타 - 헤드 높이: 1680 mm; 호스트 ID: 2822203; 치수 - 체적: 0.0736435 m3
2 x 기본 벽:A1-32-07A-콘크리트면정리, 바닥방수연장, 시멘트모르타르(미장용), 수성페인트(내부) (24mm):7563924 | 지상 9층 | 3048 | 2550 | 1100 | 새 구성 | 문 | EE111-엘리베이터문(20인승)_1100x2550 | 7620949 | EE111-엘리베이터문(문) | EE111-엘리베이터문(문): EE111-엘리베이터문(20인승)_1100x2550 | 4.15514 | EE111-엘리베이터문(20인승)_1100x2550 | 2 | 구속조건 - 레벨: 지상 9층; 씰 높이: 80 mm; 기타 - 헤드 높이: 2630 mm; 호스트 ID: 2822205; 치수 - 체적: 0.224818 m3
기본 벽:A1-32-07A-콘크리트면정리, 바닥방수연장, 시멘트모르타르(미장용), 수성페인트(내부) (24mm):7563926 | 지상 9층 | 3048 | 1800 | 2100 | 새 구성 | 문 | DR121-쌍여닫이문(철재, 방화문) 1800x2100mm | 7435628 | DR121-쌍여닫이문(철재, 방화문) | DR121-쌍여닫이문(철재, 방화문): DR121-쌍여닫이문(철재, 방화문) 1800x2100mm | 5.32025 | DR121-쌍여닫이문(철재, 방화문) 1800x2100mm | 2 | 구속조건 - 레벨: 지상 9층; 씰 높이: 80 mm; 기타 - 헤드 높이: 2180 mm; 호스트 ID: 2822227; 치수 - 체적: 0.146498 m3; 데이터 - 벽체 opening 면적: 3.78 m2
기본 벽:A1-32-07A-콘크리트면정리, 바닥방수연장, 시멘트모르타르(미장용), 수성페인트(내부) (24mm):7563927 | 지상 9층 | 3048 | 600 | 650 | 새 구성 | 문 | DR872-샤프트 점검구(스테인리스 스틸)_650x600 | 3614979 | DR872-샤프트 점검구(스테인리스 스틸) | DR872-샤프트 점검구(스테인리스 스틸): DR872-샤프트 점검구(스테인리스 스틸)_650x600 | 0.851649 | DR872-샤프트 점검구(스테인리스 스틸)_650x600 | 2 | 구속조건 - 레벨: 지상 9층; 씰 높이: 1200 mm; 기타 - 헤드 높이: 1800 mm; 호스트 ID: 2822229; 치수 - 체적: 0.0317935 m3
기본 벽:A1-32-07A-콘크리트면정리, 바닥방수연장, 시멘트모르타르(미장용), 수성페인트(내부) (24mm):7563927 | 지상 9층 | 3048 | 1000 | 2100 | 새 구성 | 문 | DR111-외여닫이문(철재, 일반)_유리포함 (원형)_2100x1000 | 7452354 | DR111-외여닫이문(철재,일반)_유리포함(원형) | DR111-외여닫이문(철재,일반)_유리포함(원형): DR111-외여닫이문(철재, 일반)_유리포함 (원형)_2100x1000 | 3.71966 | DR111-외여닫이문(철재, 일반)_유리포함 (원형)_2100x1000 | 2 | 구속조건 - 레벨: 지상 9층; 씰 높이: 80 mm; 기타 - 헤드 높이: 2180 mm; 호스트 ID: 2822237; 치수 - 체적: 0.116207 m3
기본 벽:A1-32-07A-콘크리트면정리, 바닥방수연장, 시멘트모르타르(미장용), 수성페인트(내부) (24mm):7563929 | 지상 9층 | 3048 | 2100 | 1000 | 새 구성 | 문 | DR111-외여닫이문(철재, 일반)_유리포함 (원형)_2100x1000 | 7452354 | DR111-외여닫이문(철재,일반)_유리포함(원형) | DR111-외여닫이문(철재,일반)_유리포함(원형): DR111-외여닫이문(철재, 일반)_유리포함 (원형)_2100x1000 | 3.71966 | DR111-외여닫이문(철재, 일반)_유리포함 (원형)_2100x1000 | 2 | 구속조건 - 레벨: 지상 9층; 씰 높이: 80 mm; 기타 - 헤드 높이: 2180 mm; 호스트 ID: 2822207; 치수 - 체적: 0.116207 m3
기본 벽:A1-32-07A-콘크리트면정리, 바닥방수연장, 시멘트모르타르(미장용), 수성페인트(내부) (24mm):7564692 | 지상 7층 | 3048 | 1600 | 650 | 새 구성 | 문 | DR872-샤프트 점검구(스테인리스 스틸)_650x1600 | 3648337 | DR872-샤프트 점검구(스테인리스 스틸) | DR872-샤프트 점검구(스테인리스 스틸): DR872-샤프트 점검구(스테인리스 스틸)_650x1600 | 1.90665 | DR872-샤프트 점검구(스테인리스 스틸)_650x1600 | 2 | 구속조건 - 레벨: 지상 7층; 씰 높이: 80 mm; 기타 - 헤드 높이: 1680 mm; 호스트 ID: 2821673; 치수 - 체적: 0.0736435 m3
기본 벽:A1-32-07A-콘크리트면정리, 바닥방수연장, 시멘트모르타르(미장용), 수성페인트(내부) (24mm):7564823 | 지상 8층 | 3048 | 1600 | 650 | 새 구성 | 문 | DR872-샤프트 점검구(스테인리스 스틸)_650x1600 | 3648337 | DR872-샤프트 점검구(스테인리스 스틸) | DR872-샤프트 점검구(스테인리스 스틸): DR872-샤프트 점검구(스테인리스 스틸)_650x1600 | 1.90665 | DR872-샤프트 점검구(스테인리스 스틸)_650x1600 | 2 | 구속조건 - 레벨: 지상 8층; 씰 높이: 80 mm; 기타 - 헤드 높이: 1680 mm; 호스트 ID: 2822019; 치수 - 체적: 0.0736435 m3
기본 벽:A1-32-07A-콘크리트면정리, 바닥방수연장, 시멘트모르타르(미장용), 수성페인트(내부) (24mm):7564825 | 지상 9층 | 3048 | 1600 | 650 | 새 구성 | 문 | DR872-샤프트 점검구(스테인리스 스틸)_650x1600 | 3648337 | DR872-샤프트 점검구(스테인리스 스틸) | DR872-샤프트 점검구(스테인리스 스틸): DR872-샤프트 점검구(스테인리스 스틸)_650x1600 | 1.90665 | DR872-샤프트 점검구(스테인리스 스틸)_650x1600 | 2 | 구속조건 - 레벨: 지상 9층; 씰 높이: 80 mm; 기타 - 헤드 높이: 1680 mm; 호스트 ID: 2822225; 치수 - 체적: 0.0736435 m3
기본 벽:A1-32-06A-콘크리트면정리, 시멘트모르타르(미장용), 수성페인트(내부) (18mm):7567220:1 | 지상 9층 | 2900 | 5500 | 17.3671 |  |  |  |  |  |  |  | A1-32-06A-콘크리트면정리, 시멘트모르타르(미장용), 수성페인트(내부) (18mm) | 2
기본 벽:A1-32-06A-콘크리트면정리, 시멘트모르타르(미장용), 수성페인트(내부) (18mm):7567228:1 | 지상 9층 | 2900 | 2082 | 17.3671 |  |  |  |  |  |  |  | A1-32-06A-콘크리트면정리, 시멘트모르타르(미장용), 수성페인트(내부) (18mm) | 2
기본 벽:A1-32-06A-콘크리트면정리, 시멘트모르타르(미장용), 수성페인트(내부) (18mm):7567230 | 지상 9층 | 3048 | 1100 | 2550 | 새 구성 | 문 | EE111-엘리베이터문(13인승)_1100x2550 | 7620945 | EE111-엘리베이터문(문) | EE111-엘리베이터문(문): EE111-엘리베이터문(13인승)_1100x2550 | 4.15514 | EE111-엘리베이터문(13인승)_1100x2550 | 2 | 구속조건 - 레벨: 지상 9층; 씰 높이: 80 mm; 기타 - 헤드 높이: 2630 mm; 호스트 ID: 2822221; 치수 - 체적: 0.224818 m3
기본 벽:A1-32-06A-콘크리트면정리, 시멘트모르타르(미장용), 수성페인트(내부) (18mm):7567235 | 지상 9층 | 3048 | 1600 | 1500 | 새 구성 | 창 | WD842-2단 하부 더블 프로젝트 창(스테인리스 스틸)_1500x1600mm | 7468499 | WD842-2단 하부 더블 프로젝트 창(스테인리스 스틸) | WD842-2단 하부 더블 프로젝트 창(스테인리스 스틸): WD842-2단 하부 더블 프로젝트 창(스테인리스 스틸)_1500x1600mm | 3.60783 | WD842-2단 하부 더블 프로젝트 창(스테인리스 스틸)_1500x1600mm | 2 | 구속조건 - 레벨: 지상 9층; 씰 높이: 1000 mm; 기타 - 창의개폐비: 100; 헤드 높이: 2600 mm; 호스트 ID: 6000137; 치수 - 체적: 0.084837 m3
기본 벽:A1-32-06A-콘크리트면정리, 시멘트모르타르(미장용), 수성페인트(내부) (18mm):7567287 | 지상 9층 | 3048 | 2000 | 1800 | 새 구성 | 창 | WD842-2단 하부 더블 프로젝트 창(스테인리스 스틸)_2000x1800mm | 7468501 | WD842-2단 하부 더블 프로젝트 창(스테인리스 스틸) | WD842-2단 하부 더블 프로젝트 창(스테인리스 스틸): WD842-2단 하부 더블 프로젝트 창(스테인리스 스틸)_2000x1800mm | 5.10973 | WD842-2단 하부 더블 프로젝트 창(스테인리스 스틸)_2000x1800mm | 2 | 구속조건 - 레벨: 지상 9층; 씰 높이: 1000 mm; 기타 - 창의개폐비: 100; 헤드 높이: 2800 mm; 호스트 ID: 2822243; 치수 - 체적: 0.113019 m3
기본 벽:A1-32-06A-콘크리트면정리, 시멘트모르타르(미장용), 수성페인트(내부) (18mm):7568165 | 지상 1층 | 322.8 | 3520 | 2593.15 | 새 구성 | 벽 | CW112-스테인리스 스틸 커튼월 | 7675291 | 커튼월 | 커튼월: CW112-스테인리스 스틸 커튼월 | 9.1279 | CW112-스테인리스 스틸 커튼월 | 2 | ID 데이터 - 마크: 24; 해설: SSD; 구속조건 - 매스와 관련됨: no; 룸 경계: yes; 벽 베이스가 부착됩니다.: no; 상단이 부착됩니다.: no; 베이스 구속조건: 지상 1층; 상단 구속조건: 상위 레벨: 지상 2층; 미연결 높이: 3520 mm; 베이스 간격띄우기: 80 mm; 상단 간격띄우기: -1200 mm; 구조 - 구조: no; 구조적 용도: 비교좌장치; 단면형상 정의 - 단면형상: 수직; 수직 그리드 - 각도: 0 deg; 간격띄우기: 0 mm; 맞춤: 시작; 번호: 4; sets with these values: 2; 치수 - 길이: 2693.15 mm
기본 벽:A1-32-06A-콘크리트면정리, 시멘트모르타르(미장용), 수성페인트(내부) (18mm):7568166 | 지상 1층 | 322.8 | 3520 | 6599.98 | 새 구성 | 벽 | CW112-스테인리스 스틸 커튼월 | 7675291 | 커튼월 | 커튼월: CW112-스테인리스 스틸 커튼월 | 23.2319 | CW112-스테인리스 스틸 커튼월 | 2 | ID 데이터 - 마크: 23; 해설: SSD; 구속조건 - 매스와 관련됨: no; 룸 경계: yes; 벽 베이스가 부착됩니다.: no; 상단이 부착됩니다.: no; 베이스 구속조건: 지상 1층; 상단 구속조건: 상위 레벨: 지상 2층; 미연결 높이: 3520 mm; 베이스 간격띄우기: 80 mm; 상단 간격띄우기: -1200 mm; 구조 - 구조: no; 구조적 용도: 비교좌장치; 단면형상 정의 - 단면형상: 수직; 수직 그리드 - 각도: 0 deg; 간격띄우기: 0 mm; 맞춤: 시작; 번호: 4; sets with these values: 2; 치수 - 길이: 6599.98 mm
기본 벽:A1-32-06A-콘크리트면정리, 시멘트모르타르(미장용), 수성페인트(내부) (18mm):7568171 | 지상 1층 | 322.8 | 3520 | 9000 | 새 구성 | 벽 | CW112-스테인리스 스틸 커튼월 | 7675291 | 커튼월 | 커튼월: CW112-스테인리스 스틸 커튼월 | 31.68 | CW112-스테인리스 스틸 커튼월 | 2 | ID 데이터 - 마크: 18; 해설: SSD; 구속조건 - 매스와 관련됨: no; 룸 경계: yes; 벽 베이스가 부착됩니다.: no; 상단이 부착됩니다.: no; 베이스 구속조건: 지상 1층; 상단 구속조건: 상위 레벨: 지상 2층; 미연결 높이: 3520 mm; 베이스 간격띄우기: 80 mm; 상단 간격띄우기: -1200 mm; 구조 - 구조: no; 구조적 용도: 비교좌장치; 단면형상 정의 - 단면형상: 수직; 수직 그리드 - 각도: 0 deg; 간격띄우기: 0 mm; 맞춤: 시작; 번호: 4; sets with these values: 2; 치수 - 길이: 9000 mm
기본 벽:A1-32-06A-콘크리트면정리, 시멘트모르타르(미장용), 수성페인트(내부) (18mm):7568171 | 지상 1층 | 322.8 | 9900 | 3520 | 새 구성 | 벽 | CW112-스테인리스 스틸 커튼월 | 7675291 | 커튼월 | 커튼월: CW112-스테인리스 스틸 커튼월 | 34.848 | CW112-스테인리스 스틸 커튼월 | 2 | ID 데이터 - 마크: 22; 해설: SSD; 구속조건 - 매스와 관련됨: no; 룸 경계: yes; 벽 베이스가 부착됩니다.: no; 상단이 부착됩니다.: no; 베이스 구속조건: 지상 1층; 상단 구속조건: 상위 레벨: 지상 2층; 미연결 높이: 3520 mm; 베이스 간격띄우기: 80 mm; 상단 간격띄우기: -1200 mm; 구조 - 구조: no; 구조적 용도: 비교좌장치; 단면형상 정의 - 단면형상: 수직; 수직 그리드 - 각도: 0 deg; 간격띄우기: 0 mm; 맞춤: 시작; 번호: 4; sets with these values: 2; 치수 - 길이: 9900 mm
기본 벽:A1-32-06A-콘크리트면정리, 시멘트모르타르(미장용), 수성페인트(내부) (18mm):7568172 | 지상 1층 | 322.8 | 7487.49 | 3380 | 새 구성 | 벽 | CW112-스테인리스 스틸 커튼월 | 7675291 | 커튼월 | 커튼월: CW112-스테인리스 스틸 커튼월 | 25.3077 | CW112-스테인리스 스틸 커튼월 | 2 | ID 데이터 - 마크: 19; 해설: SSD; 구속조건 - 매스와 관련됨: no; 룸 경계: yes; 벽 베이스가 부착됩니다.: no; 상단이 부착됩니다.: no; 베이스 구속조건: 지상 1층; 상단 구속조건: 상위 레벨: 지상 2층; 미연결 높이: 4800 mm; 베이스 간격띄우기: 0 mm; 상단 간격띄우기: 0 mm; 구조 - 구조: no; 구조적 용도: 비교좌장치; 단면형상 정의 - 단면형상: 수직; 수직 그리드 - 각도: 0 deg; 간격띄우기: 0 mm; 맞춤: 시작; 번호: 4; sets with these values: 2; 치수 - 길이: 7487.49 mm
기본 벽:A1-32-06A-콘크리트면정리, 시멘트모르타르(미장용), 수성페인트(내부) (18mm):7568173 | 지상 1층 | 3048 | 2100 | 1100 | 새 구성 | 문 | DR111-외여닫이문(철재, 일반) 1100x2100mm 2 | 8088344 | DR111-외여닫이문(철재, 일반) | DR111-외여닫이문(철재, 일반): DR111-외여닫이문(철재, 일반) 1100x2100mm 2 | 3.66584 | DR111-외여닫이문(철재, 일반) 1100x2100mm 2 | 2 | 구속조건 - 레벨: 지상 1층; 씰 높이: 80 mm; 기타 - 헤드 높이: 2180 mm; 호스트 ID: 2818910; 치수 - 벽체 opening 면적: 2.31 m2; 체적: 0.122657 m3
기본 벽:A1-32-06A-콘크리트면정리, 시멘트모르타르(미장용), 수성페인트(내부) (18mm):7568173 | 지상 1층 | 3048 | 600 | 650 | 새 구성 | 문 | DR872-샤프트 점검구(스테인리스 스틸)_650x600 | 3614979 | DR872-샤프트 점검구(스테인리스 스틸) | DR872-샤프트 점검구(스테인리스 스틸): DR872-샤프트 점검구(스테인리스 스틸)_650x600 | 0.851649 | DR872-샤프트 점검구(스테인리스 스틸)_650x600 | 2 | 구속조건 - 레벨: 지상 1층; 씰 높이: 650 mm; 기타 - 헤드 높이: 1250 mm; 호스트 ID: 2818910; 치수 - 체적: 0.0317935 m3
기본 벽:A1-32-06A-콘크리트면정리, 시멘트모르타르(미장용), 수성페인트(내부) (18mm):7568173 | 지상 1층 | 3048 | 1000 | 2100 | 새 구성 | 문 | DR111-외여닫이문(철재, 일반)_유리포함 (원형)_2100x1000 | 7452354 | DR111-외여닫이문(철재,일반)_유리포함(원형) | DR111-외여닫이문(철재,일반)_유리포함(원형): DR111-외여닫이문(철재, 일반)_유리포함 (원형)_2100x1000 | 3.71966 | DR111-외여닫이문(철재, 일반)_유리포함 (원형)_2100x1000 | 2 | 구속조건 - 레벨: 지상 1층; 씰 높이: -470 mm; 기타 - 헤드 높이: 1630 mm; 호스트 ID: 2819152; 치수 - 체적: 0.116207 m3
기본 벽:A1-32-06A-콘크리트면정리, 시멘트모르타르(미장용), 수성페인트(내부) (18mm):7568174 | 지상 1층 | 3048 | 2100 | 1000 | 새 구성 | 문 | DR111-외여닫이문(철재, 일반)_유리포함 (원형)_2100x1000 | 7452354 | DR111-외여닫이문(철재,일반)_유리포함(원형) | DR111-외여닫이문(철재,일반)_유리포함(원형): DR111-외여닫이문(철재, 일반)_유리포함 (원형)_2100x1000 | 3.71966 | DR111-외여닫이문(철재, 일반)_유리포함 (원형)_2100x1000 | 2 | 구속조건 - 레벨: 지상 1층; 씰 높이: -470 mm; 기타 - 헤드 높이: 1630 mm; 호스트 ID: 2818043; 치수 - 체적: 0.116207 m3
기본 벽:A1-32-06A-콘크리트면정리, 시멘트모르타르(미장용), 수성페인트(내부) (18mm):7568176 | 지상 1층 | 3048 | 1600 | 650 | 새 구성 | 문 | DR872-샤프트 점검구(스테인리스 스틸)_650x1600 | 3648337 | DR872-샤프트 점검구(스테인리스 스틸) | DR872-샤프트 점검구(스테인리스 스틸): DR872-샤프트 점검구(스테인리스 스틸)_650x1600 | 1.90665 | DR872-샤프트 점검구(스테인리스 스틸)_650x1600 | 2 | 구속조건 - 레벨: 지상 1층; 씰 높이: 0 mm; 기타 - 헤드 높이: 1600 mm; 호스트 ID: 2818536; 치수 - 체적: 0.0736435 m3
2 x 기본 벽:A1-32-06A-콘크리트면정리, 시멘트모르타르(미장용), 수성페인트(내부) (18mm):7568177 | 지상 1층 | 3048 | 2550 | 1100 | 새 구성 | 문 | EE111-엘리베이터문(20인승)_1100x2550 | 7620949 | EE111-엘리베이터문(문) | EE111-엘리베이터문(문): EE111-엘리베이터문(20인승)_1100x2550 | 4.15514 | EE111-엘리베이터문(20인승)_1100x2550 | 2 | 구속조건 - 레벨: 지상 1층; 씰 높이: 80 mm; 기타 - 헤드 높이: 2630 mm; 호스트 ID: 2818041; 치수 - 체적: 0.224818 m3
기본 벽:A1-32-06A-콘크리트면정리, 시멘트모르타르(미장용), 수성페인트(내부) (18mm):7568178 | 지상 1층 | 3048 | 1100 | 2100 | 새 구성 | 문 | DR111-외여닫이문(철재, 일반) 1100x2100mm 2 | 8088344 | DR111-외여닫이문(철재, 일반) | DR111-외여닫이문(철재, 일반): DR111-외여닫이문(철재, 일반) 1100x2100mm 2 | 3.66584 | DR111-외여닫이문(철재, 일반) 1100x2100mm 2 | 2 | 구속조건 - 레벨: 지상 1층; 씰 높이: 80 mm; 기타 - 헤드 높이: 2180 mm; 호스트 ID: 2818039; 치수 - 벽체 opening 면적: 2.31 m2; 체적: 0.122657 m3
기본 벽:A1-32-06A-콘크리트면정리, 시멘트모르타르(미장용), 수성페인트(내부) (18mm):7568178 | 지상 1층 | 3048 | 900 | 2100 | 새 구성 | 문 | DR111-외여닫이문(철재, 일반) 900x2100mm | 7447208 | DR111-외여닫이문(철재, 일반) | DR111-외여닫이문(철재, 일반): DR111-외여닫이문(철재, 일반) 900x2100mm | 3.19384 | DR111-외여닫이문(철재, 일반) 900x2100mm | 2 | 구속조건 - 레벨: 지상 1층; 씰 높이: 80 mm; 기타 - 헤드 높이: 2180 mm; 호스트 ID: 2818039; 치수 - 벽체 opening 면적: 1.89 m2; 체적: 0.108017 m3
기본 벽:A1-32-06A-콘크리트면정리, 시멘트모르타르(미장용), 수성페인트(내부) (18mm):7568179 | 지상 1층 | 322.8 | 1200 | 3520 | 새 구성 | 벽 | CW112-스테인리스 스틸 커튼월 | 7675291 | 커튼월 | 커튼월: CW112-스테인리스 스틸 커튼월 | 4.224 | CW112-스테인리스 스틸 커튼월 | 2 | ID 데이터 - 마크: 14; 해설: SSD; 구속조건 - 매스와 관련됨: no; 룸 경계: yes; 벽 베이스가 부착됩니다.: no; 상단이 부착됩니다.: no; 베이스 구속조건: 지상 1층; 상단 구속조건: 상위 레벨: 지상 2층; 미연결 높이: 3520 mm; 베이스 간격띄우기: 80 mm; 상단 간격띄우기: -1200 mm; 구조 - 구조: no; 구조적 용도: 비교좌장치; 단면형상 정의 - 단면형상: 수직; 수직 그리드 - 각도: 0 deg; 간격띄우기: 0 mm; 맞춤: 시작; 번호: 4; sets with these values: 2; 치수 - 길이: 1200 mm
기본 벽:A1-32-06A-콘크리트면정리, 시멘트모르타르(미장용), 수성페인트(내부) (18mm):7568179 | 지상 1층 | 3048 | 1800 | 2000 | 새 구성 | 창 | WD842-2단 하부 더블 프로젝트 창(스테인리스 스틸)_2000x1800mm | 7468501 | WD842-2단 하부 더블 프로젝트 창(스테인리스 스틸) | WD842-2단 하부 더블 프로젝트 창(스테인리스 스틸): WD842-2단 하부 더블 프로젝트 창(스테인리스 스틸)_2000x1800mm | 5.10973 | WD842-2단 하부 더블 프로젝트 창(스테인리스 스틸)_2000x1800mm | 2 | 구속조건 - 레벨: 지상 1층; 씰 높이: 1000 mm; 기타 - 창의개폐비: 100; 헤드 높이: 2800 mm; 호스트 ID: 2818398; 치수 - 체적: 0.113019 m3
기본 벽:A1-32-06A-콘크리트면정리, 시멘트모르타르(미장용), 수성페인트(내부) (18mm):7568186 | 지상 1층 | 3048 | 1500 | 1600 | 새 구성 | 창 | WD842-2단 하부 더블 프로젝트 창(스테인리스 스틸)_1500x1600mm | 7468499 | WD842-2단 하부 더블 프로젝트 창(스테인리스 스틸) | WD842-2단 하부 더블 프로젝트 창(스테인리스 스틸): WD842-2단 하부 더블 프로젝트 창(스테인리스 스틸)_1500x1600mm | 3.60783 | WD842-2단 하부 더블 프로젝트 창(스테인리스 스틸)_1500x1600mm | 2 | 구속조건 - 레벨: 지상 1층; 씰 높이: 1000 mm; 기타 - 창의개폐비: 100; 헤드 높이: 2600 mm; 호스트 ID: 5342341; 치수 - 체적: 0.084837 m3
기본 벽:A1-32-06A-콘크리트면정리, 시멘트모르타르(미장용), 수성페인트(내부) (18mm):7568255 | 지상 1층 | 322.8 | 3380 | 7487.49 | 새 구성 | 벽 | CW112-스테인리스 스틸 커튼월 | 7675291 | 커튼월 | 커튼월: CW112-스테인리스 스틸 커튼월 | 25.3077 | CW112-스테인리스 스틸 커튼월 | 2 | ID 데이터 - 마크: 19; 해설: SSD; 구속조건 - 매스와 관련됨: no; 룸 경계: yes; 벽 베이스가 부착됩니다.: no; 상단이 부착됩니다.: no; 베이스 구속조건: 지상 1층; 상단 구속조건: 상위 레벨: 지상 2층; 미연결 높이: 4800 mm; 베이스 간격띄우기: 0 mm; 상단 간격띄우기: 0 mm; 구조 - 구조: no; 구조적 용도: 비교좌장치; 단면형상 정의 - 단면형상: 수직; 수직 그리드 - 각도: 0 deg; 간격띄우기: 0 mm; 맞춤: 시작; 번호: 4; sets with these values: 2; 치수 - 길이: 7487.49 mm
기본 벽:A1-32-06A-콘크리트면정리, 시멘트모르타르(미장용), 수성페인트(내부) (18mm):7568269 | 지상 1층 | 3048 | 2000 | 1800 | 새 구성 | 창 | WD842-2단 하부 더블 프로젝트 창(스테인리스 스틸)_2000x1800mm | 7468501 | WD842-2단 하부 더블 프로젝트 창(스테인리스 스틸) | WD842-2단 하부 더블 프로젝트 창(스테인리스 스틸): WD842-2단 하부 더블 프로젝트 창(스테인리스 스틸)_2000x1800mm | 5.10973 | WD842-2단 하부 더블 프로젝트 창(스테인리스 스틸)_2000x1800mm | 2 | 구속조건 - 레벨: 지상 1층; 씰 높이: -500 mm; 기타 - 창의개폐비: 100; 헤드 높이: 1300 mm; 호스트 ID: 2819460; 치수 - 체적: 0.113019 m3
기본 벽:A1-32-06A-콘크리트면정리, 시멘트모르타르(미장용), 수성페인트(내부) (18mm):7568273 | 지상 1층 | 3048 | 1100 | 2550 | 새 구성 | 문 | EE111-엘리베이터문(13인승)_1100x2550 | 7620945 | EE111-엘리베이터문(문) | EE111-엘리베이터문(문): EE111-엘리베이터문(13인승)_1100x2550 | 4.15514 | EE111-엘리베이터문(13인승)_1100x2550 | 2 | 구속조건 - 레벨: 지상 1층; 씰 높이: 80 mm; 기타 - 헤드 높이: 2630 mm; 호스트 ID: 2818057; 치수 - 체적: 0.224818 m3
기본 벽:A1-32-06A-콘크리트면정리, 시멘트모르타르(미장용), 수성페인트(내부) (18mm):7568275 | 지상 1층 | 3048 | 900 | 2100 | 새 구성 | 문 | DR111-외여닫이문(철재, 일반) 900x2100mm | 7447208 | DR111-외여닫이문(철재, 일반) | DR111-외여닫이문(철재, 일반): DR111-외여닫이문(철재, 일반) 900x2100mm | 3.19384 | DR111-외여닫이문(철재, 일반) 900x2100mm | 2 | 구속조건 - 레벨: 지상 1층; 씰 높이: 80 mm; 기타 - 헤드 높이: 2180 mm; 호스트 ID: 2818039; 치수 - 벽체 opening 면적: 1.89 m2; 체적: 0.108017 m3
기본 벽:A1-32-06A-콘크리트면정리, 시멘트모르타르(미장용), 수성페인트(내부) (18mm):7568276 | 지상 1층 | 3048 | 1100 | 2100 | 새 구성 | 문 | DR111-외여닫이문(철재, 일반) 1100x2100mm 2 | 8088344 | DR111-외여닫이문(철재, 일반) | DR111-외여닫이문(철재, 일반): DR111-외여닫이문(철재, 일반) 1100x2100mm 2 | 3.66584 | DR111-외여닫이문(철재, 일반) 1100x2100mm 2 | 2 | 구속조건 - 레벨: 지상 1층; 씰 높이: 80 mm; 기타 - 헤드 높이: 2180 mm; 호스트 ID: 2818039; 치수 - 벽체 opening 면적: 2.31 m2; 체적: 0.122657 m3
기본 벽:A1-32-06A-콘크리트면정리, 시멘트모르타르(미장용), 수성페인트(내부) (18mm):7568280 | 지하1층 | 3048 | 2100 | 1100 | 새 구성 | 문 | DR111-외여닫이문(철재, 일반) 1100x2100mm 2 | 8088344 | DR111-외여닫이문(철재, 일반) | DR111-외여닫이문(철재, 일반): DR111-외여닫이문(철재, 일반) 1100x2100mm 2 | 3.66584 | DR111-외여닫이문(철재, 일반) 1100x2100mm 2 | 2 | 구속조건 - 레벨: 지하1층; 씰 높이: 200 mm; 기타 - 헤드 높이: 2300 mm; 호스트 ID: 2816471; 치수 - 벽체 opening 면적: 2.31 m2; 체적: 0.122657 m3
기본 벽:A1-32-06A-콘크리트면정리, 시멘트모르타르(미장용), 수성페인트(내부) (18mm):7568287 | 지상 1층 | 3048 | 2100 | 1100 | 새 구성 | 문 | DR111-외여닫이문(철재, 일반) 1100x2100mm 2 | 8088344 | DR111-외여닫이문(철재, 일반) | DR111-외여닫이문(철재, 일반): DR111-외여닫이문(철재, 일반) 1100x2100mm 2 | 3.66584 | DR111-외여닫이문(철재, 일반) 1100x2100mm 2 | 2 | 구속조건 - 레벨: 지상 1층; 씰 높이: 80 mm; 기타 - 헤드 높이: 2180 mm; 호스트 ID: 2818910; 치수 - 벽체 opening 면적: 2.31 m2; 체적: 0.122657 m3
기본 벽:A1-33-01B-시멘트 모르타르, 도기질타일 (30mm):7573902 | 지상 1층 | 3048 | 800 | 1200 | 새 구성 | 창 | WD812-미들창(스테인리스 스틸) 하부개폐 800x1200mm | 7464739 | WD812-미들창(스테인리스 스틸) | WD812-미들창(스테인리스 스틸): WD812-미들창(스테인리스 스틸) 하부개폐 800x1200mm | 1.62992 | WD812-미들창(스테인리스 스틸) 하부개폐 800x1200mm | 2 | 구속조건 - 레벨: 지상 1층; 씰 높이: 400 mm; 기타 - 창의개폐비: 50; 헤드 높이: 1600 mm; 호스트 ID: 2818037; 치수 - 벽체 opening 면적: 0.96 m2; 체적: 0.0421992 m3
기본 벽:A1-33-01B-시멘트 모르타르, 도기질타일 (30mm):7573905 | 지상 1층 | 3048 | 650 | 600 | 새 구성 | 문 | DR872-샤프트 점검구(스테인리스 스틸)_650x600 | 3614979 | DR872-샤프트 점검구(스테인리스 스틸) | DR872-샤프트 점검구(스테인리스 스틸): DR872-샤프트 점검구(스테인리스 스틸)_650x600 | 0.851649 | DR872-샤프트 점검구(스테인리스 스틸)_650x600 | 2 | 구속조건 - 레벨: 지상 1층; 씰 높이: 600 mm; 기타 - 헤드 높이: 1200 mm; 호스트 ID: 2818912; 치수 - 체적: 0.0317935 m3
기본 벽:A1-33-01B-시멘트 모르타르, 도기질타일 (30mm):7573908 | 지상 1층 | 3048 | 1000 | 2100 | 새 구성 | 문 | DR111-외여닫이문(철재, 일반)_유리포함 (원형)_2100x1000 | 7452354 | DR111-외여닫이문(철재,일반)_유리포함(원형) | DR111-외여닫이문(철재,일반)_유리포함(원형): DR111-외여닫이문(철재, 일반)_유리포함 (원형)_2100x1000 | 3.71966 | DR111-외여닫이문(철재, 일반)_유리포함 (원형)_2100x1000 | 2 | 구속조건 - 레벨: 지상 1층; 씰 높이: -470 mm; 기타 - 헤드 높이: 1630 mm; 호스트 ID: 2819152; 치수 - 체적: 0.116207 m3
기본 벽:A1-32-06A-콘크리트면정리, 시멘트모르타르(미장용), 수성페인트(내부) (18mm):7576669 | 옥탑층 | 3048 | 1100 | 2100 | 새 구성 | 문 | DR111-외여닫이문(철재, 일반) 1100x2100mm 2 | 8088344 | DR111-외여닫이문(철재, 일반) | DR111-외여닫이문(철재, 일반): DR111-외여닫이문(철재, 일반) 1100x2100mm 2 | 3.66584 | DR111-외여닫이문(철재, 일반) 1100x2100mm 2 | 2 | 구속조건 - 레벨: 옥탑층; 씰 높이: 80 mm; 기타 - 헤드 높이: 2180 mm; 호스트 ID: 2822839; 치수 - 벽체 opening 면적: 2.31 m2; 체적: 0.122657 m3
기본 벽:A1-32-06A-콘크리트면정리, 시멘트모르타르(미장용), 수성페인트(내부) (18mm):7576670 | 옥탑층 | 3048 | 1800 | 2100 | 새 구성 | 문 | DR121-쌍여닫이문(철재, 방화문) 1800x2100mm | 7435628 | DR121-쌍여닫이문(철재, 방화문) | DR121-쌍여닫이문(철재, 방화문): DR121-쌍여닫이문(철재, 방화문) 1800x2100mm | 5.32025 | DR121-쌍여닫이문(철재, 방화문) 1800x2100mm | 2 | 구속조건 - 레벨: 옥탑층; 씰 높이: 80 mm; 기타 - 헤드 높이: 2180 mm; 호스트 ID: 2822815; 치수 - 체적: 0.146498 m3; 데이터 - 벽체 opening 면적: 3.78 m2
기본 벽:A1-32-07A-콘크리트면정리, 바닥방수연장, 시멘트모르타르(미장용), 수성페인트(내부) (24mm):7697856 | 지상 9층 | 3048 | 900 | 2100 | 새 구성 | 문 | DR111-외여닫이문(철재, 일반) 900x2100mm | 7447208 | DR111-외여닫이문(철재, 일반) | DR111-외여닫이문(철재, 일반): DR111-외여닫이문(철재, 일반) 900x2100mm | 3.19384 | DR111-외여닫이문(철재, 일반) 900x2100mm | 2 | 구속조건 - 레벨: 지상 9층; 씰 높이: 80 mm; 기타 - 헤드 높이: 2180 mm; 호스트 ID: 5903103; 치수 - 벽체 opening 면적: 1.89 m2; 체적: 0.108017 m3
기본 벽:A1-33-01B-시멘트 모르타르, 도기질타일 (30mm):7705231 | 지상 2층 | 3048 | 1000 | 2100 | 새 구성 | 문 | DR111-외여닫이문(철재, 일반)_유리포함 (원형)_2100x1000 | 7452354 | DR111-외여닫이문(철재,일반)_유리포함(원형) | DR111-외여닫이문(철재,일반)_유리포함(원형): DR111-외여닫이문(철재, 일반)_유리포함 (원형)_2100x1000 | 3.71966 | DR111-외여닫이문(철재, 일반)_유리포함 (원형)_2100x1000 | 2 | 구속조건 - 레벨: 지상 2층; 씰 높이: 80 mm; 기타 - 헤드 높이: 2180 mm; 호스트 ID: 2820028; 치수 - 체적: 0.116207 m3
기본 벽:A1-33-01B-시멘트 모르타르, 도기질타일 (30mm):7705232 | 지상 2층 | 3048 | 800 | 1200 | 새 구성 | 창 | WD812-미들창(스테인리스 스틸) 하부개폐 800x1200mm | 7464739 | WD812-미들창(스테인리스 스틸) | WD812-미들창(스테인리스 스틸): WD812-미들창(스테인리스 스틸) 하부개폐 800x1200mm | 1.62992 | WD812-미들창(스테인리스 스틸) 하부개폐 800x1200mm | 2 | 구속조건 - 레벨: 지상 2층; 씰 높이: 1200 mm; 기타 - 창의개폐비: 50; 헤드 높이: 2400 mm; 호스트 ID: 2820022; 치수 - 벽체 opening 면적: 0.96 m2; 체적: 0.0421992 m3
기본 벽:A1-33-01B-시멘트 모르타르, 도기질타일 (30mm):7705527 | 지상 3층 | 3048 | 1000 | 2100 | 새 구성 | 문 | DR111-외여닫이문(철재, 일반)_유리포함 (원형)_2100x1000 | 7452354 | DR111-외여닫이문(철재,일반)_유리포함(원형) | DR111-외여닫이문(철재,일반)_유리포함(원형): DR111-외여닫이문(철재, 일반)_유리포함 (원형)_2100x1000 | 3.71966 | DR111-외여닫이문(철재, 일반)_유리포함 (원형)_2100x1000 | 2 | 구속조건 - 레벨: 지상 3층; 씰 높이: 80 mm; 기타 - 헤드 높이: 2180 mm; 호스트 ID: 2820447; 치수 - 체적: 0.116207 m3
기본 벽:A1-33-01B-시멘트 모르타르, 도기질타일 (30mm):7705528 | 지상 3층 | 3048 | 800 | 1200 | 새 구성 | 창 | WD812-미들창(스테인리스 스틸) 하부개폐 800x1200mm | 7464739 | WD812-미들창(스테인리스 스틸) | WD812-미들창(스테인리스 스틸): WD812-미들창(스테인리스 스틸) 하부개폐 800x1200mm | 1.62992 | WD812-미들창(스테인리스 스틸) 하부개폐 800x1200mm | 2 | 구속조건 - 레벨: 지상 3층; 씰 높이: 1200 mm; 기타 - 창의개폐비: 50; 헤드 높이: 2400 mm; 호스트 ID: 2820441; 치수 - 벽체 opening 면적: 0.96 m2; 체적: 0.0421992 m3
기본 벽:A1-33-01B-시멘트 모르타르, 도기질타일 (30mm):7705536 | 지상 4층 | 3048 | 1000 | 2100 | 새 구성 | 문 | DR111-외여닫이문(철재, 일반)_유리포함 (원형)_2100x1000 | 7452354 | DR111-외여닫이문(철재,일반)_유리포함(원형) | DR111-외여닫이문(철재,일반)_유리포함(원형): DR111-외여닫이문(철재, 일반)_유리포함 (원형)_2100x1000 | 3.71966 | DR111-외여닫이문(철재, 일반)_유리포함 (원형)_2100x1000 | 2 | 구속조건 - 레벨: 지상 4층; 씰 높이: 80 mm; 기타 - 헤드 높이: 2180 mm; 호스트 ID: 2820697; 치수 - 체적: 0.116207 m3
기본 벽:A1-33-01B-시멘트 모르타르, 도기질타일 (30mm):7705537 | 지상 4층 | 3048 | 800 | 1200 | 새 구성 | 창 | WD812-미들창(스테인리스 스틸) 하부개폐 800x1200mm | 7464739 | WD812-미들창(스테인리스 스틸) | WD812-미들창(스테인리스 스틸): WD812-미들창(스테인리스 스틸) 하부개폐 800x1200mm | 1.62992 | WD812-미들창(스테인리스 스틸) 하부개폐 800x1200mm | 2 | 구속조건 - 레벨: 지상 4층; 씰 높이: 1200 mm; 기타 - 창의개폐비: 50; 헤드 높이: 2400 mm; 호스트 ID: 2820691; 치수 - 벽체 opening 면적: 0.96 m2; 체적: 0.0421992 m3
기본 벽:A1-33-01B-시멘트 모르타르, 도기질타일 (30mm):7705545 | 지상 5층 | 3048 | 1000 | 2100 | 새 구성 | 문 | DR111-외여닫이문(철재, 일반)_유리포함 (원형)_2100x1000 | 7452354 | DR111-외여닫이문(철재,일반)_유리포함(원형) | DR111-외여닫이문(철재,일반)_유리포함(원형): DR111-외여닫이문(철재, 일반)_유리포함 (원형)_2100x1000 | 3.71966 | DR111-외여닫이문(철재, 일반)_유리포함 (원형)_2100x1000 | 2 | 구속조건 - 레벨: 지상 5층; 씰 높이: 80 mm; 기타 - 헤드 높이: 2180 mm; 호스트 ID: 2821199; 치수 - 체적: 0.116207 m3
기본 벽:A1-33-01B-시멘트 모르타르, 도기질타일 (30mm):7705546 | 지상 5층 | 3048 | 800 | 1200 | 새 구성 | 창 | WD812-미들창(스테인리스 스틸) 하부개폐 800x1200mm | 7464739 | WD812-미들창(스테인리스 스틸) | WD812-미들창(스테인리스 스틸): WD812-미들창(스테인리스 스틸) 하부개폐 800x1200mm | 1.62992 | WD812-미들창(스테인리스 스틸) 하부개폐 800x1200mm | 2 | 구속조건 - 레벨: 지상 5층; 씰 높이: 1200 mm; 기타 - 창의개폐비: 50; 헤드 높이: 2400 mm; 호스트 ID: 2821193; 치수 - 벽체 opening 면적: 0.96 m2; 체적: 0.0421992 m3
기본 벽:A1-33-01B-시멘트 모르타르, 도기질타일 (30mm):7705554 | 지상 6층 | 3048 | 1000 | 2100 | 새 구성 | 문 | DR111-외여닫이문(철재, 일반)_유리포함 (원형)_2100x1000 | 7452354 | DR111-외여닫이문(철재,일반)_유리포함(원형) | DR111-외여닫이문(철재,일반)_유리포함(원형): DR111-외여닫이문(철재, 일반)_유리포함 (원형)_2100x1000 | 3.71966 | DR111-외여닫이문(철재, 일반)_유리포함 (원형)_2100x1000 | 2 | 구속조건 - 레벨: 지상 6층; 씰 높이: 80 mm; 기타 - 헤드 높이: 2180 mm; 호스트 ID: 2821459; 치수 - 체적: 0.116207 m3
기본 벽:A1-33-01B-시멘트 모르타르, 도기질타일 (30mm):7705555 | 지상 6층 | 3048 | 800 | 1200 | 새 구성 | 창 | WD812-미들창(스테인리스 스틸) 하부개폐 800x1200mm | 7464739 | WD812-미들창(스테인리스 스틸) | WD812-미들창(스테인리스 스틸): WD812-미들창(스테인리스 스틸) 하부개폐 800x1200mm | 1.62992 | WD812-미들창(스테인리스 스틸) 하부개폐 800x1200mm | 2 | 구속조건 - 레벨: 지상 6층; 씰 높이: 1200 mm; 기타 - 창의개폐비: 50; 헤드 높이: 2400 mm; 호스트 ID: 2821453; 치수 - 벽체 opening 면적: 0.96 m2; 체적: 0.0421992 m3
기본 벽:A1-33-01B-시멘트 모르타르, 도기질타일 (30mm):7705563 | 지상 7층 | 3048 | 1000 | 2100 | 새 구성 | 문 | DR111-외여닫이문(철재, 일반)_유리포함 (원형)_2100x1000 | 7452354 | DR111-외여닫이문(철재,일반)_유리포함(원형) | DR111-외여닫이문(철재,일반)_유리포함(원형): DR111-외여닫이문(철재, 일반)_유리포함 (원형)_2100x1000 | 3.71966 | DR111-외여닫이문(철재, 일반)_유리포함 (원형)_2100x1000 | 2 | 구속조건 - 레벨: 지상 7층; 씰 높이: 80 mm; 기타 - 헤드 높이: 2180 mm; 호스트 ID: 2821655; 치수 - 체적: 0.116207 m3
기본 벽:A1-33-01B-시멘트 모르타르, 도기질타일 (30mm):7705564 | 지상 7층 | 3048 | 800 | 1200 | 새 구성 | 창 | WD812-미들창(스테인리스 스틸) 하부개폐 800x1200mm | 7464739 | WD812-미들창(스테인리스 스틸) | WD812-미들창(스테인리스 스틸): WD812-미들창(스테인리스 스틸) 하부개폐 800x1200mm | 1.62992 | WD812-미들창(스테인리스 스틸) 하부개폐 800x1200mm | 2 | 구속조건 - 레벨: 지상 7층; 씰 높이: 1200 mm; 기타 - 창의개폐비: 50; 헤드 높이: 2400 mm; 호스트 ID: 2821649; 치수 - 벽체 opening 면적: 0.96 m2; 체적: 0.0421992 m3
기본 벽:A1-33-01B-시멘트 모르타르, 도기질타일 (30mm):7705572 | 지상 8층 | 3048 | 2100 | 1000 | 새 구성 | 문 | DR111-외여닫이문(철재, 일반)_유리포함 (원형)_2100x1000 | 7452354 | DR111-외여닫이문(철재,일반)_유리포함(원형) | DR111-외여닫이문(철재,일반)_유리포함(원형): DR111-외여닫이문(철재, 일반)_유리포함 (원형)_2100x1000 | 3.71966 | DR111-외여닫이문(철재, 일반)_유리포함 (원형)_2100x1000 | 2 | 구속조건 - 레벨: 지상 8층; 씰 높이: 80 mm; 기타 - 헤드 높이: 2180 mm; 호스트 ID: 2822001; 치수 - 체적: 0.116207 m3
기본 벽:A1-33-01B-시멘트 모르타르, 도기질타일 (30mm):7705573 | 지상 8층 | 3048 | 800 | 1200 | 새 구성 | 창 | WD812-미들창(스테인리스 스틸) 하부개폐 800x1200mm | 7464739 | WD812-미들창(스테인리스 스틸) | WD812-미들창(스테인리스 스틸): WD812-미들창(스테인리스 스틸) 하부개폐 800x1200mm | 1.62992 | WD812-미들창(스테인리스 스틸) 하부개폐 800x1200mm | 2 | 구속조건 - 레벨: 지상 8층; 씰 높이: 1200 mm; 기타 - 창의개폐비: 50; 헤드 높이: 2400 mm; 호스트 ID: 2821995; 치수 - 벽체 opening 면적: 0.96 m2; 체적: 0.0421992 m3
기본 벽:A1-33-01B-시멘트 모르타르, 도기질타일 (30mm):7705581 | 지상 9층 | 3048 | 1000 | 2100 | 새 구성 | 문 | DR111-외여닫이문(철재, 일반)_유리포함 (원형)_2100x1000 | 7452354 | DR111-외여닫이문(철재,일반)_유리포함(원형) | DR111-외여닫이문(철재,일반)_유리포함(원형): DR111-외여닫이문(철재, 일반)_유리포함 (원형)_2100x1000 | 3.71966 | DR111-외여닫이문(철재, 일반)_유리포함 (원형)_2100x1000 | 2 | 구속조건 - 레벨: 지상 9층; 씰 높이: 80 mm; 기타 - 헤드 높이: 2180 mm; 호스트 ID: 2822207; 치수 - 체적: 0.116207 m3
기본 벽:A1-33-01B-시멘트 모르타르, 도기질타일 (30mm):7705582 | 지상 9층 | 3048 | 800 | 1200 | 새 구성 | 창 | WD812-미들창(스테인리스 스틸) 하부개폐 800x1200mm | 7464739 | WD812-미들창(스테인리스 스틸) | WD812-미들창(스테인리스 스틸): WD812-미들창(스테인리스 스틸) 하부개폐 800x1200mm | 1.62992 | WD812-미들창(스테인리스 스틸) 하부개폐 800x1200mm | 2 | 구속조건 - 레벨: 지상 9층; 씰 높이: 1200 mm; 기타 - 창의개폐비: 50; 헤드 높이: 2400 mm; 호스트 ID: 2822201; 치수 - 벽체 opening 면적: 0.96 m2; 체적: 0.0421992 m3
기본 벽:A1-33-01B-시멘트 모르타르, 도기질타일 (30mm):7707329 | 지상 2층 | 3048 | 1000 | 2100 | 새 구성 | 문 | DR111-외여닫이문(철재, 일반)_유리포함 (원형)_2100x1000 | 7452354 | DR111-외여닫이문(철재,일반)_유리포함(원형) | DR111-외여닫이문(철재,일반)_유리포함(원형): DR111-외여닫이문(철재, 일반)_유리포함 (원형)_2100x1000 | 3.71966 | DR111-외여닫이문(철재, 일반)_유리포함 (원형)_2100x1000 | 2 | 구속조건 - 레벨: 지상 2층; 씰 높이: 80 mm; 기타 - 헤드 높이: 2180 mm; 호스트 ID: 2820060; 치수 - 체적: 0.116207 m3
기본 벽:A1-33-01B-시멘트 모르타르, 도기질타일 (30mm):7707513 | 지상 3층 | 3048 | 1000 | 2100 | 새 구성 | 문 | DR111-외여닫이문(철재, 일반)_유리포함 (원형)_2100x1000 | 7452354 | DR111-외여닫이문(철재,일반)_유리포함(원형) | DR111-외여닫이문(철재,일반)_유리포함(원형): DR111-외여닫이문(철재, 일반)_유리포함 (원형)_2100x1000 | 3.71966 | DR111-외여닫이문(철재, 일반)_유리포함 (원형)_2100x1000 | 2 | 구속조건 - 레벨: 지상 3층; 씰 높이: 80 mm; 기타 - 헤드 높이: 2180 mm; 호스트 ID: 2820477; 치수 - 체적: 0.116207 m3
기본 벽:A1-33-01B-시멘트 모르타르, 도기질타일 (30mm):7707517 | 지상 4층 | 3048 | 1000 | 2100 | 새 구성 | 문 | DR111-외여닫이문(철재, 일반)_유리포함 (원형)_2100x1000 | 7452354 | DR111-외여닫이문(철재,일반)_유리포함(원형) | DR111-외여닫이문(철재,일반)_유리포함(원형): DR111-외여닫이문(철재, 일반)_유리포함 (원형)_2100x1000 | 3.71966 | DR111-외여닫이문(철재, 일반)_유리포함 (원형)_2100x1000 | 2 | 구속조건 - 레벨: 지상 4층; 씰 높이: 80 mm; 기타 - 헤드 높이: 2180 mm; 호스트 ID: 2820727; 치수 - 체적: 0.116207 m3
기본 벽:A1-33-01B-시멘트 모르타르, 도기질타일 (30mm):7707521 | 지상 5층 | 3048 | 1000 | 2100 | 새 구성 | 문 | DR111-외여닫이문(철재, 일반)_유리포함 (원형)_2100x1000 | 7452354 | DR111-외여닫이문(철재,일반)_유리포함(원형) | DR111-외여닫이문(철재,일반)_유리포함(원형): DR111-외여닫이문(철재, 일반)_유리포함 (원형)_2100x1000 | 3.71966 | DR111-외여닫이문(철재, 일반)_유리포함 (원형)_2100x1000 | 2 | 구속조건 - 레벨: 지상 5층; 씰 높이: 80 mm; 기타 - 헤드 높이: 2180 mm; 호스트 ID: 2821229; 치수 - 체적: 0.116207 m3
기본 벽:A1-33-01B-시멘트 모르타르, 도기질타일 (30mm):7707525 | 지상 6층 | 3048 | 1000 | 2100 | 새 구성 | 문 | DR111-외여닫이문(철재, 일반)_유리포함 (원형)_2100x1000 | 7452354 | DR111-외여닫이문(철재,일반)_유리포함(원형) | DR111-외여닫이문(철재,일반)_유리포함(원형): DR111-외여닫이문(철재, 일반)_유리포함 (원형)_2100x1000 | 3.71966 | DR111-외여닫이문(철재, 일반)_유리포함 (원형)_2100x1000 | 2 | 구속조건 - 레벨: 지상 6층; 씰 높이: 80 mm; 기타 - 헤드 높이: 2180 mm; 호스트 ID: 2821489; 치수 - 체적: 0.116207 m3
기본 벽:A1-33-01B-시멘트 모르타르, 도기질타일 (30mm):7707529 | 지상 7층 | 3048 | 1000 | 2100 | 새 구성 | 문 | DR111-외여닫이문(철재, 일반)_유리포함 (원형)_2100x1000 | 7452354 | DR111-외여닫이문(철재,일반)_유리포함(원형) | DR111-외여닫이문(철재,일반)_유리포함(원형): DR111-외여닫이문(철재, 일반)_유리포함 (원형)_2100x1000 | 3.71966 | DR111-외여닫이문(철재, 일반)_유리포함 (원형)_2100x1000 | 2 | 구속조건 - 레벨: 지상 7층; 씰 높이: 80 mm; 기타 - 헤드 높이: 2180 mm; 호스트 ID: 2821685; 치수 - 체적: 0.116207 m3
기본 벽:A1-33-01B-시멘트 모르타르, 도기질타일 (30mm):7707533 | 지상 8층 | 3048 | 1000 | 2100 | 새 구성 | 문 | DR111-외여닫이문(철재, 일반)_유리포함 (원형)_2100x1000 | 7452354 | DR111-외여닫이문(철재,일반)_유리포함(원형) | DR111-외여닫이문(철재,일반)_유리포함(원형): DR111-외여닫이문(철재, 일반)_유리포함 (원형)_2100x1000 | 3.71966 | DR111-외여닫이문(철재, 일반)_유리포함 (원형)_2100x1000 | 2 | 구속조건 - 레벨: 지상 8층; 씰 높이: 80 mm; 기타 - 헤드 높이: 2180 mm; 호스트 ID: 2822031; 치수 - 체적: 0.116207 m3
기본 벽:A1-33-01B-시멘트 모르타르, 도기질타일 (30mm):7707537 | 지상 9층 | 3048 | 1000 | 2100 | 새 구성 | 문 | DR111-외여닫이문(철재, 일반)_유리포함 (원형)_2100x1000 | 7452354 | DR111-외여닫이문(철재,일반)_유리포함(원형) | DR111-외여닫이문(철재,일반)_유리포함(원형): DR111-외여닫이문(철재, 일반)_유리포함 (원형)_2100x1000 | 3.71966 | DR111-외여닫이문(철재, 일반)_유리포함 (원형)_2100x1000 | 2 | 구속조건 - 레벨: 지상 9층; 씰 높이: 80 mm; 기타 - 헤드 높이: 2180 mm; 호스트 ID: 2822237; 치수 - 체적: 0.116207 m3
기본 벽:A1-33-01B-시멘트 모르타르, 도기질타일 (30mm):7708203 | 지상 2층 | 3048 | 650 | 600 | 새 구성 | 문 | DR872-샤프트 점검구(스테인리스 스틸)_650x600 | 3614979 | DR872-샤프트 점검구(스테인리스 스틸) | DR872-샤프트 점검구(스테인리스 스틸): DR872-샤프트 점검구(스테인리스 스틸)_650x600 | 0.851649 | DR872-샤프트 점검구(스테인리스 스틸)_650x600 | 2 | 구속조건 - 레벨: 지상 2층; 씰 높이: 1200 mm; 기타 - 헤드 높이: 1800 mm; 호스트 ID: 2820054; 치수 - 체적: 0.0317935 m3
기본 벽:A1-33-01B-시멘트 모르타르, 도기질타일 (30mm):7708262 | 지상 3층 | 3048 | 650 | 600 | 새 구성 | 문 | DR872-샤프트 점검구(스테인리스 스틸)_650x600 | 3614979 | DR872-샤프트 점검구(스테인리스 스틸) | DR872-샤프트 점검구(스테인리스 스틸): DR872-샤프트 점검구(스테인리스 스틸)_650x600 | 0.851649 | DR872-샤프트 점검구(스테인리스 스틸)_650x600 | 2 | 구속조건 - 레벨: 지상 3층; 씰 높이: 1200 mm; 기타 - 헤드 높이: 1800 mm; 호스트 ID: 2820471; 치수 - 체적: 0.0317935 m3
기본 벽:A1-33-01B-시멘트 모르타르, 도기질타일 (30mm):7708264 | 지상 4층 | 3048 | 650 | 600 | 새 구성 | 문 | DR872-샤프트 점검구(스테인리스 스틸)_650x600 | 3614979 | DR872-샤프트 점검구(스테인리스 스틸) | DR872-샤프트 점검구(스테인리스 스틸): DR872-샤프트 점검구(스테인리스 스틸)_650x600 | 0.851649 | DR872-샤프트 점검구(스테인리스 스틸)_650x600 | 2 | 구속조건 - 레벨: 지상 4층; 씰 높이: 1200 mm; 기타 - 헤드 높이: 1800 mm; 호스트 ID: 2820721; 치수 - 체적: 0.0317935 m3
기본 벽:A1-33-01B-시멘트 모르타르, 도기질타일 (30mm):7708266 | 지상 5층 | 3048 | 650 | 600 | 새 구성 | 문 | DR872-샤프트 점검구(스테인리스 스틸)_650x600 | 3614979 | DR872-샤프트 점검구(스테인리스 스틸) | DR872-샤프트 점검구(스테인리스 스틸): DR872-샤프트 점검구(스테인리스 스틸)_650x600 | 0.851649 | DR872-샤프트 점검구(스테인리스 스틸)_650x600 | 2 | 구속조건 - 레벨: 지상 5층; 씰 높이: 1200 mm; 기타 - 헤드 높이: 1800 mm; 호스트 ID: 2821223; 치수 - 체적: 0.0317935 m3
기본 벽:A1-33-01B-시멘트 모르타르, 도기질타일 (30mm):7708268 | 지상 6층 | 3048 | 650 | 600 | 새 구성 | 문 | DR872-샤프트 점검구(스테인리스 스틸)_650x600 | 3614979 | DR872-샤프트 점검구(스테인리스 스틸) | DR872-샤프트 점검구(스테인리스 스틸): DR872-샤프트 점검구(스테인리스 스틸)_650x600 | 0.851649 | DR872-샤프트 점검구(스테인리스 스틸)_650x600 | 2 | 구속조건 - 레벨: 지상 6층; 씰 높이: 1200 mm; 기타 - 헤드 높이: 1800 mm; 호스트 ID: 2821483; 치수 - 체적: 0.0317935 m3
기본 벽:A1-33-01B-시멘트 모르타르, 도기질타일 (30mm):7708270 | 지상 7층 | 3048 | 650 | 600 | 새 구성 | 문 | DR872-샤프트 점검구(스테인리스 스틸)_650x600 | 3614979 | DR872-샤프트 점검구(스테인리스 스틸) | DR872-샤프트 점검구(스테인리스 스틸): DR872-샤프트 점검구(스테인리스 스틸)_650x600 | 0.851649 | DR872-샤프트 점검구(스테인리스 스틸)_650x600 | 2 | 구속조건 - 레벨: 지상 7층; 씰 높이: 1200 mm; 기타 - 헤드 높이: 1800 mm; 호스트 ID: 2821679; 치수 - 체적: 0.0317935 m3
기본 벽:A1-33-01B-시멘트 모르타르, 도기질타일 (30mm):7708272 | 지상 8층 | 3048 | 650 | 600 | 새 구성 | 문 | DR872-샤프트 점검구(스테인리스 스틸)_650x600 | 3614979 | DR872-샤프트 점검구(스테인리스 스틸) | DR872-샤프트 점검구(스테인리스 스틸): DR872-샤프트 점검구(스테인리스 스틸)_650x600 | 0.851649 | DR872-샤프트 점검구(스테인리스 스틸)_650x600 | 2 | 구속조건 - 레벨: 지상 8층; 씰 높이: 1200 mm; 기타 - 헤드 높이: 1800 mm; 호스트 ID: 2822025; 치수 - 체적: 0.0317935 m3
기본 벽:A1-33-01B-시멘트 모르타르, 도기질타일 (30mm):7708274 | 지상 9층 | 3048 | 650 | 600 | 새 구성 | 문 | DR872-샤프트 점검구(스테인리스 스틸)_650x600 | 3614979 | DR872-샤프트 점검구(스테인리스 스틸) | DR872-샤프트 점검구(스테인리스 스틸): DR872-샤프트 점검구(스테인리스 스틸)_650x600 | 0.851649 | DR872-샤프트 점검구(스테인리스 스틸)_650x600 | 2 | 구속조건 - 레벨: 지상 9층; 씰 높이: 1200 mm; 기타 - 헤드 높이: 1800 mm; 호스트 ID: 2822231; 치수 - 체적: 0.0317935 m3
기본 벽:A1-32-07A-콘크리트면정리, 바닥방수연장, 시멘트모르타르(미장용), 수성페인트(내부) (24mm):7727693 | 지상 3층 | 3048 | 2100 | 1000 | 새 구성 | 문 | DR111-외여닫이문(철재, 일반)_유리포함 (원형)_2100x1000 | 7452354 | DR111-외여닫이문(철재,일반)_유리포함(원형) | DR111-외여닫이문(철재,일반)_유리포함(원형): DR111-외여닫이문(철재, 일반)_유리포함 (원형)_2100x1000 | 3.71966 | DR111-외여닫이문(철재, 일반)_유리포함 (원형)_2100x1000 | 2 | 구속조건 - 레벨: 지상 3층; 씰 높이: 80 mm; 기타 - 헤드 높이: 2180 mm; 호스트 ID: 2820447; 치수 - 체적: 0.116207 m3
기본 벽:A1-32-06A-콘크리트면정리, 시멘트모르타르(미장용), 수성페인트(내부) (18mm):7743669 | 지상 1층 | 322.8 | 3520 | 10700 | 새 구성 | 벽 | CW112-스테인리스 스틸 커튼월 | 7675291 | 커튼월 | 커튼월: CW112-스테인리스 스틸 커튼월 | 37.664 | CW112-스테인리스 스틸 커튼월 | 2 | ID 데이터 - 마크: 20; 해설: SSD; 구속조건 - 매스와 관련됨: no; 룸 경계: yes; 벽 베이스가 부착됩니다.: no; 상단이 부착됩니다.: no; 베이스 구속조건: 지상 1층; 상단 구속조건: 상위 레벨: 지상 2층; 미연결 높이: 3520 mm; 베이스 간격띄우기: 80 mm; 상단 간격띄우기: -1200 mm; 구조 - 구조: no; 구조적 용도: 비교좌장치; 단면형상 정의 - 단면형상: 수직; 수직 그리드 - 각도: 0 deg; 간격띄우기: 0 mm; 맞춤: 시작; 번호: 4; sets with these values: 2; 치수 - 길이: 10700 mm
기본 벽:WA211-시멘트벽돌(일반) 벽 (0.5B) 90mm:7796598 | 지상 1층 | 394.8 | 3929.98 | 3520 | 새 구성 | 벽 | CW112-스테인리스 스틸 커튼월 | 7675291 | 커튼월 | 커튼월: CW112-스테인리스 스틸 커튼월 | 13.8335 | CW112-스테인리스 스틸 커튼월 | 2 | ID 데이터 - 마크: 24; 해설: SSD; 구속조건 - 매스와 관련됨: no; 룸 경계: yes; 벽 베이스가 부착됩니다.: no; 상단이 부착됩니다.: no; 베이스 구속조건: 지상 1층; 상단 구속조건: 상위 레벨: 지상 2층; 미연결 높이: 3520 mm; 베이스 간격띄우기: 80 mm; 상단 간격띄우기: -1200 mm; 구조 - 구조: no; 구조적 용도: 비교좌장치; 단면형상 정의 - 단면형상: 수직; 수직 그리드 - 각도: 0 deg; 간격띄우기: 0 mm; 맞춤: 시작; 번호: 4; sets with these values: 2; 치수 - 길이: 3929.98 mm
기본 벽:A1-32-06A-콘크리트면정리, 시멘트모르타르(미장용), 수성페인트(내부) (18mm):7822344 | 지상 9층 | 3048 | 2100 | 900 | 새 구성 | 문 | DR111-외여닫이문(철재, 일반) 900x2100mm | 7447208 | DR111-외여닫이문(철재, 일반) | DR111-외여닫이문(철재, 일반): DR111-외여닫이문(철재, 일반) 900x2100mm | 3.19384 | DR111-외여닫이문(철재, 일반) 900x2100mm | 2 | 구속조건 - 레벨: 지상 9층; 씰 높이: 80 mm; 기타 - 헤드 높이: 2180 mm; 호스트 ID: 5903103; 치수 - 벽체 opening 면적: 1.89 m2; 체적: 0.108017 m3
기본 벽:A1-32-06A-콘크리트면정리, 시멘트모르타르(미장용), 수성페인트(내부) (18mm):8045457 | 지상 9층 | 3048 | 1800 | 2100 | 새 구성 | 문 | DR121-쌍여닫이문(철재, 방화문) 1800x2100mm | 7435628 | DR121-쌍여닫이문(철재, 방화문) | DR121-쌍여닫이문(철재, 방화문): DR121-쌍여닫이문(철재, 방화문) 1800x2100mm | 5.32025 | DR121-쌍여닫이문(철재, 방화문) 1800x2100mm | 2 | 구속조건 - 레벨: 지상 9층; 씰 높이: 80 mm; 기타 - 헤드 높이: 2180 mm; 호스트 ID: 2822227; 치수 - 체적: 0.146498 m3; 데이터 - 벽체 opening 면적: 3.78 m2
WD733-그릴창(알루미늄):WD733-그릴창(알루미늄)_600x800mm:2980428:1 | 지하2층 | 200 | 600 | 800
WD733-그릴창(알루미늄):WD733-그릴창(알루미늄)_600x800mm:2980429:1 | 지하2층 | 200 | 600 | 800
DR121-쌍여닫이문(철재, 방화문):DR121-쌍여닫이문(철재, 방화문) 1800x2100mm:3048116:1 | 지하2층 | 200 | 1800 | 2100
기본 벽:WA111-철근콘크리트구조 벽 200mm_W1:2815051 | 지하2층 | 3048 | 1800 | 2100
DR121-쌍여닫이문(철재, 방화문):DR121-쌍여닫이문(철재, 방화문) 1800x2100mm:3048500:1 | 지하2층 | 200 | 1800 | 2100
기본 벽:WA111-철근콘크리트구조 벽 200mm_W1:2815303 | 지하2층 | 3048 | 1800 | 2100
DR121-쌍여닫이문(철재, 방화문):DR121-쌍여닫이문(철재, 방화문) 1800x2100mm:3154184:1 | 지하2층 | 200 | 1800 | 2100
DR121-쌍여닫이문(철재, 방화문):DR121-쌍여닫이문(철재, 방화문) 1800x2100mm:3054000:1 | 지하1층 | 200 | 1800 | 2100
DR111-외여닫이문(철재, 일반):DR111-외여닫이문(철재, 일반) 900x2100mm:3174688:1 | 지하1층 | 200 | 900 | 2100
DR111-외여닫이문(철재, 일반):DR111-외여닫이문(철재, 일반) 1100x2100mm 2:3046012:1 | 지하1층 | 200 | 1100 | 2100
WD733-그릴창(알루미늄):WD733-그릴창(알루미늄)_600x800mm:2980336:1 | 지하1층 | 200 | 600 | 800
WD733-그릴창(알루미늄):WD733-그릴창(알루미늄)_600x800mm:2980337:1 | 지하1층 | 200 | 600 | 800
DR121-쌍여닫이문(철재, 방화문):DR121-쌍여닫이문(철재, 방화문) 1800x2100mm:3054616:1 | 지하1층 | 200 | 1800 | 2100
EE111-엘리베이터문(문):EE111-엘리베이터문(20인승)_1100x2550:3838630:1 | 지상 1층 | 200 | 1100 | 2550
EE111-엘리베이터문(문):EE111-엘리베이터문(20인승)_1100x2550:3838757:1 | 지상 1층 | 200 | 1100 | 2550
WD733-그릴창(알루미늄):WD733-그릴창(알루미늄)_600x800mm:2979508:1 | 지상 1층 | 200 | 600 | 800
WD733-그릴창(알루미늄):WD733-그릴창(알루미늄)_600x800mm:2979509:1 | 지상 1층 | 200 | 600 | 800
WD733-그릴창(알루미늄):WD733-그릴창(알루미늄)_600x800mm:3190340:1 | 지상 1층 | 200 | 600 | 800
WD733-그릴창(알루미늄):WD733-그릴창(알루미늄)_600x800mm:3190516:1 | 지상 1층 | 200 | 600 | 800
WD842-2단 하부 더블 프로젝트 창(스테인리스 스틸):WD842-2단 하부 더블 프로젝트 창(스테인리스 스틸)_2000x1800mm:5433460:1 | 지상 1층 | 200 | 2000 | 1800
DR872-샤프트 점검구(스테인리스 스틸):DR872-샤프트 점검구(스테인리스 스틸)_650x1600:5918487:1 | 지상 1층 | 200 | 650 | 1600
DR111-외여닫이문(철재, 일반):DR111-외여닫이문(철재, 일반) 1100x2100mm 2:3081194:1 | 지상 1층 | 200 | 1100 | 2100
DR872-샤프트 점검구(스테인리스 스틸):DR872-샤프트 점검구(스테인리스 스틸)_650x600:5878498:1 | 지상 1층 | 200 | 650 | 600
DR872-샤프트 점검구(스테인리스 스틸):DR872-샤프트 점검구(스테인리스 스틸)_650x600:3081304:1 | 지상 1층 | 200 | 650 | 600
DR111-외여닫이문(철재,일반)_유리포함(원형):DR111-외여닫이문(철재, 일반)_유리포함 (원형)_2100x1000:3171737:1 | 지상 1층 | 200 | 1000 | 2100
WD842-2단 하부 더블 프로젝트 창(스테인리스 스틸):WD842-2단 하부 더블 프로젝트 창(스테인리스 스틸)_2000x1800mm:5916752:1 | 지상 1층 | 200 | 2000 | 1800
WD812-미들창(스테인리스 스틸):WD812-미들창(스테인리스 스틸) 하부개폐 1000x1600mm:5438364:1 | 지상 2층 | 200 | 1000 | 1600
WD812-미들창(스테인리스 스틸):WD812-미들창(스테인리스 스틸) 하부개폐 800x1200mm:5458595:1 | 지상 2층 | 200 | 800 | 1200
DR111-외여닫이문(철재, 일반):DR111-외여닫이문(철재, 일반) 900x2100mm:3081612:1 | 지상 2층 | 200 | 900 | 2100
DR111-외여닫이문(철재, 일반):DR111-외여닫이문(철재, 일반) 1100x2100mm 2:3158107:1 | 지상 2층 | 200 | 1100 | 2100
DR872-샤프트 점검구(스테인리스 스틸):DR872-샤프트 점검구(스테인리스 스틸)_650x1600:3648486:1 | 지상 2층 | 200 | 650 | 1600
EE111-엘리베이터문(문):EE111-엘리베이터문(20인승)_1100x2550:3839172:1 | 지상 2층 | 200 | 1100 | 2550
EE111-엘리베이터문(문):EE111-엘리베이터문(20인승)_1100x2550:3839171:1 | 지상 2층 | 200 | 1100 | 2550
DR111-외여닫이문(철재,일반)_유리포함(원형):DR111-외여닫이문(철재, 일반)_유리포함 (원형)_2100x1000:3171448:1 | 지상 2층 | 200 | 1000 | 2100
WD733-그릴창(알루미늄):WD733-그릴창(알루미늄)_600x800mm:2976935:1 | 지상 2층 | 200 | 600 | 800
WD733-그릴창(알루미늄):WD733-그릴창(알루미늄)_600x800mm:2979348:1 | 지상 2층 | 200 | 600 | 800
WD842-2단 하부 더블 프로젝트 창(스테인리스 스틸):WD842-2단 하부 더블 프로젝트 창(스테인리스 스틸)_2000x1800mm:5433619:1 | 지상 2층 | 200 | 2000 | 1800
DR872-샤프트 점검구(스테인리스 스틸):DR872-샤프트 점검구(스테인리스 스틸)_650x1600:3648487:1 | 지상 2층 | 200 | 650 | 1600
DR121-쌍여닫이문(철재, 방화문):DR121-쌍여닫이문(철재, 방화문) 1800x2100mm:3081811:1 | 지상 2층 | 200 | 1800 | 2100
DR872-샤프트 점검구(스테인리스 스틸):DR872-샤프트 점검구(스테인리스 스틸)_650x600:3648488:1 | 지상 2층 | 200 | 650 | 600
DR872-샤프트 점검구(스테인리스 스틸):DR872-샤프트 점검구(스테인리스 스틸)_650x600:3081354:1 | 지상 2층 | 200 | 650 | 600
DR111-외여닫이문(철재,일반)_유리포함(원형):DR111-외여닫이문(철재, 일반)_유리포함 (원형)_2100x1000:3171595:1 | 지상 2층 | 200 | 1000 | 2100
WD812-미들창(스테인리스 스틸):WD812-미들창(스테인리스 스틸) 하부개폐 1000x1600mm:5438115:1 | 지상 3층 | 200 | 1000 | 1600
WD812-미들창(스테인리스 스틸):WD812-미들창(스테인리스 스틸) 하부개폐 800x1200mm:5438394:1 | 지상 3층 | 200 | 800 | 1200
DR111-외여닫이문(철재,일반)_유리포함(원형):DR111-외여닫이문(철재, 일반)_유리포함 (원형)_2100x1000:3171745:1 | 지상 3층 | 200 | 1000 | 2100
WD733-그릴창(알루미늄):WD733-그릴창(알루미늄)_600x800mm:2979600:1 | 지상 3층 | 200 | 600 | 800
WD733-그릴창(알루미늄):WD733-그릴창(알루미늄)_600x800mm:2979601:1 | 지상 3층 | 200 | 600 | 800
WD842-2단 하부 더블 프로젝트 창(스테인리스 스틸):WD842-2단 하부 더블 프로젝트 창(스테인리스 스틸)_2000x1800mm:5433621:1 | 지상 3층 | 200 | 2000 | 1800
DR872-샤프트 점검구(스테인리스 스틸):DR872-샤프트 점검구(스테인리스 스틸)_650x600:3081361:1 | 지상 3층 | 200 | 650 | 600
DR872-샤프트 점검구(스테인리스 스틸):DR872-샤프트 점검구(스테인리스 스틸)_650x600:3081362:1 | 지상 3층 | 200 | 650 | 600
DR111-외여닫이문(철재,일반)_유리포함(원형):DR111-외여닫이문(철재, 일반)_유리포함 (원형)_2100x1000:3171746:1 | 지상 3층 | 200 | 1000 | 2100
WD812-미들창(스테인리스 스틸):WD812-미들창(스테인리스 스틸) 하부개폐 1000x1600mm:5438282:1 | 지상 4층 | 200 | 1000 | 1600
WD812-미들창(스테인리스 스틸):WD812-미들창(스테인리스 스틸) 하부개폐 800x1200mm:5458597:1 | 지상 4층 | 200 | 800 | 1200
DR111-외여닫이문(철재, 일반):DR111-외여닫이문(철재, 일반) 900x2100mm:3081624:1 | 지상 4층 | 200 | 900 | 2100
DR111-외여닫이문(철재, 일반):DR111-외여닫이문(철재, 일반) 1100x2100mm 2:3158117:1 | 지상 4층 | 200 | 1100 | 2100
DR872-샤프트 점검구(스테인리스 스틸):DR872-샤프트 점검구(스테인리스 스틸)_650x1600:3648499:1 | 지상 4층 | 200 | 650 | 1600
EE111-엘리베이터문(문):EE111-엘리베이터문(20인승)_1100x2550:3839223:1 | 지상 4층 | 200 | 1100 | 2550
EE111-엘리베이터문(문):EE111-엘리베이터문(20인승)_1100x2550:3839222:1 | 지상 4층 | 200 | 1100 | 2550
WD733-그릴창(알루미늄):WD733-그릴창(알루미늄)_600x800mm:2979692:1 | 지상 4층 | 200 | 600 | 800
WD733-그릴창(알루미늄):WD733-그릴창(알루미늄)_600x800mm:2979693:1 | 지상 4층 | 200 | 600 | 800
WD842-2단 하부 더블 프로젝트 창(스테인리스 스틸):WD842-2단 하부 더블 프로젝트 창(스테인리스 스틸)_2000x1800mm:5433352:1 | 지상 4층 | 200 | 2000 | 1800
DR872-샤프트 점검구(스테인리스 스틸):DR872-샤프트 점검구(스테인리스 스틸)_650x1600:3648500:1 | 지상 4층 | 200 | 650 | 1600
DR121-쌍여닫이문(철재, 방화문):DR121-쌍여닫이문(철재, 방화문) 1800x2100mm:3081923:1 | 지상 4층 | 200 | 1800 | 2100
DR872-샤프트 점검구(스테인리스 스틸):DR872-샤프트 점검구(스테인리스 스틸)_650x600:3648501:1 | 지상 4층 | 200 | 650 | 600
DR872-샤프트 점검구(스테인리스 스틸):DR872-샤프트 점검구(스테인리스 스틸)_650x600:3081370:1 | 지상 4층 | 200 | 650 | 600
DR111-외여닫이문(철재,일반)_유리포함(원형):DR111-외여닫이문(철재, 일반)_유리포함 (원형)_2100x1000:3171755:1 | 지상 4층 | 200 | 1000 | 2100
DR111-외여닫이문(철재, 일반, 양개):DR111-외여닫이문(유리, 일반, 양개) 925x1970mm 2:7695852:1 | 지상 4층 | 200 | 925 | 1970
WD842-2단 하부 더블 프로젝트 창(스테인리스 스틸):WD842-2단 하부 더블 프로젝트 창(스테인리스 스틸)_2000x1800mm:5410182:1 | 지상 4층 | 200 | 2000 | 1800
WD812-미들창(스테인리스 스틸):WD812-미들창(스테인리스 스틸) 하부개폐 1000x1600mm:5438284:1 | 지상 5층 | 200 | 1000 | 1600
WD812-미들창(스테인리스 스틸):WD812-미들창(스테인리스 스틸) 하부개폐 800x1200mm:5458599:1 | 지상 5층 | 200 | 800 | 1200
EE111-엘리베이터문(문):EE111-엘리베이터문(20인승)_1100x2550:3839265:1 | 지상 5층 | 200 | 1100 | 2550
EE111-엘리베이터문(문):EE111-엘리베이터문(20인승)_1100x2550:3839264:1 | 지상 5층 | 200 | 1100 | 2550
DR111-외여닫이문(철재,일반)_유리포함(원형):DR111-외여닫이문(철재, 일반)_유리포함 (원형)_2100x1000:3171763:1 | 지상 5층 | 200 | 1000 | 2100
WD733-그릴창(알루미늄):WD733-그릴창(알루미늄)_600x800mm:2979784:1 | 지상 5층 | 200 | 600 | 800
WD733-그릴창(알루미늄):WD733-그릴창(알루미늄)_600x800mm:2979785:1 | 지상 5층 | 200 | 600 | 800
WD842-2단 하부 더블 프로젝트 창(스테인리스 스틸):WD842-2단 하부 더블 프로젝트 창(스테인리스 스틸)_2000x1800mm:5433396:1 | 지상 5층 | 200 | 2000 | 1800
DR872-샤프트 점검구(스테인리스 스틸):DR872-샤프트 점검구(스테인리스 스틸)_650x1600:3648513:1 | 지상 5층 | 200 | 650 | 1600
DR121-쌍여닫이문(철재, 방화문):DR121-쌍여닫이문(철재, 방화문) 1800x2100mm:3081929:1 | 지상 5층 | 200 | 1800 | 2100
DR872-샤프트 점검구(스테인리스 스틸):DR872-샤프트 점검구(스테인리스 스틸)_650x600:3648514:1 | 지상 5층 | 200 | 650 | 600
DR872-샤프트 점검구(스테인리스 스틸):DR872-샤프트 점검구(스테인리스 스틸)_650x600:3081378:1 | 지상 5층 | 200 | 650 | 600
DR111-외여닫이문(철재,일반)_유리포함(원형):DR111-외여닫이문(철재, 일반)_유리포함 (원형)_2100x1000:3171764:1 | 지상 5층 | 200 | 1000 | 2100
DR111-외여닫이문(철재, 일반, 양개):DR111-외여닫이문(유리, 일반, 양개) 925x1970mm 2:7695861:1 | 지상 5층 | 200 | 925 | 1970
WD842-2단 하부 더블 프로젝트 창(스테인리스 스틸):WD842-2단 하부 더블 프로젝트 창(스테인리스 스틸)_2000x1800mm:5410962:1 | 지상 5층 | 200 | 2000 | 1800
WD812-미들창(스테인리스 스틸):WD812-미들창(스테인리스 스틸) 하부개폐 1000x1600mm:5438286:1 | 지상 6층 | 200 | 1000 | 1600
WD812-미들창(스테인리스 스틸):WD812-미들창(스테인리스 스틸) 하부개폐 800x1200mm:5458601:1 | 지상 6층 | 200 | 800 | 1200
EE111-엘리베이터문(문):EE111-엘리베이터문(20인승)_1100x2550:3839307:1 | 지상 6층 | 200 | 1100 | 2550
EE111-엘리베이터문(문):EE111-엘리베이터문(20인승)_1100x2550:3839306:1 | 지상 6층 | 200 | 1100 | 2550
WD733-그릴창(알루미늄):WD733-그릴창(알루미늄)_600x800mm:2979876:1 | 지상 6층 | 200 | 600 | 800
WD733-그릴창(알루미늄):WD733-그릴창(알루미늄)_600x800mm:2979877:1 | 지상 6층 | 200 | 600 | 800
WD842-2단 하부 더블 프로젝트 창(스테인리스 스틸):WD842-2단 하부 더블 프로젝트 창(스테인리스 스틸)_2000x1800mm:5433398:1 | 지상 6층 | 200 | 2000 | 1800
DR872-샤프트 점검구(스테인리스 스틸):DR872-샤프트 점검구(스테인리스 스틸)_650x1600:3648526:1 | 지상 6층 | 200 | 650 | 1600
DR121-쌍여닫이문(철재, 방화문):DR121-쌍여닫이문(철재, 방화문) 1800x2100mm:3081935:1 | 지상 6층 | 200 | 1800 | 2100
DR872-샤프트 점검구(스테인리스 스틸):DR872-샤프트 점검구(스테인리스 스틸)_650x600:3648527:1 | 지상 6층 | 200 | 650 | 600
DR872-샤프트 점검구(스테인리스 스틸):DR872-샤프트 점검구(스테인리스 스틸)_650x600:3081386:1 | 지상 6층 | 200 | 650 | 600
DR111-외여닫이문(철재,일반)_유리포함(원형):DR111-외여닫이문(철재, 일반)_유리포함 (원형)_2100x1000:3171773:1 | 지상 6층 | 200 | 1000 | 2100
DR111-외여닫이문(철재, 일반, 양개):DR111-외여닫이문(유리, 일반, 양개) 925x1970mm 2:7695865:1 | 지상 6층 | 200 | 925 | 1970
WD842-2단 하부 더블 프로젝트 창(스테인리스 스틸):WD842-2단 하부 더블 프로젝트 창(스테인리스 스틸)_2000x1800mm:5411044:1 | 지상 6층 | 200 | 2000 | 1800
WD812-미들창(스테인리스 스틸):WD812-미들창(스테인리스 스틸) 하부개폐 1000x1600mm:5438288:1 | 지상 7층 | 200 | 1000 | 1600
WD812-미들창(스테인리스 스틸):WD812-미들창(스테인리스 스틸) 하부개폐 800x1200mm:5458603:1 | 지상 7층 | 200 | 800 | 1200
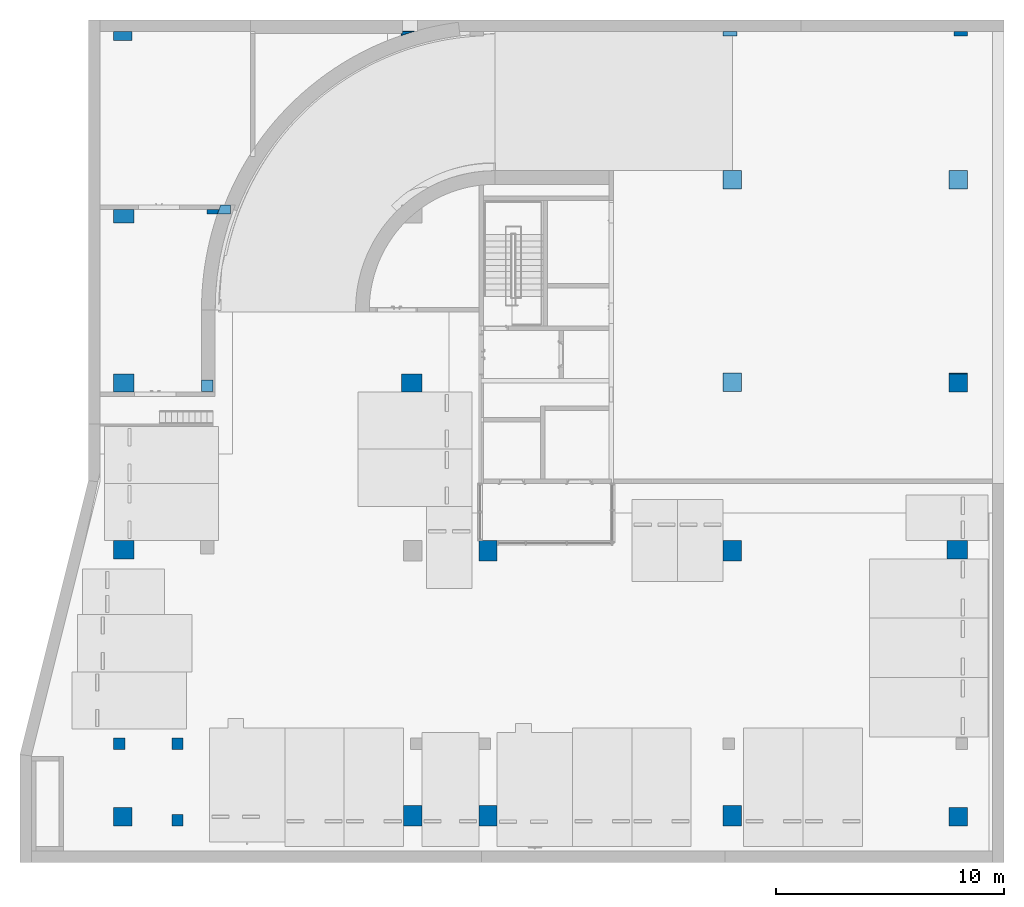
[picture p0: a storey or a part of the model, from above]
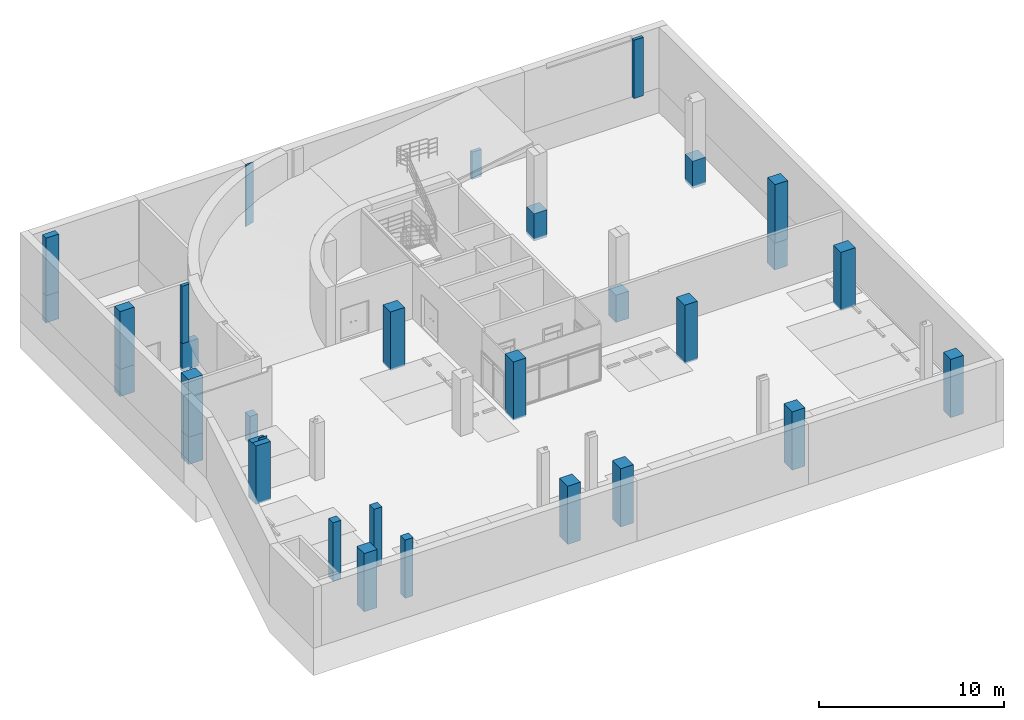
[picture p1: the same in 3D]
Properties of the parts of a building model (IFC2X3), part 28 of 39

# IfcOpeningElement: Opening (863)
Name | In | Depth (mm) | Height (mm) | Width (mm) | 생성 공정 | 카테고리 | 유형 | 유형 ID | 패밀리 | 패밀리 및 유형 | 면적 (m2) | Reference | Pset_OpeningElementCommon, sets with these values
DR111-외여닫이문(철재, 일반):DR111-외여닫이문(철재, 일반) 900x2100mm:3081642:1 | 지상 7층 | 200 | 900 | 2100
DR111-외여닫이문(철재, 일반):DR111-외여닫이문(철재, 일반) 1100x2100mm 2:3158132:1 | 지상 7층 | 200 | 1100 | 2100
DR872-샤프트 점검구(스테인리스 스틸):DR872-샤프트 점검구(스테인리스 스틸)_650x1600:3648538:1 | 지상 7층 | 200 | 650 | 1600
EE111-엘리베이터문(문):EE111-엘리베이터문(20인승)_1100x2550:3839349:1 | 지상 7층 | 200 | 1100 | 2550
EE111-엘리베이터문(문):EE111-엘리베이터문(20인승)_1100x2550:3839348:1 | 지상 7층 | 200 | 1100 | 2550
DR111-외여닫이문(철재,일반)_유리포함(원형):DR111-외여닫이문(철재, 일반)_유리포함 (원형)_2100x1000:3171781:1 | 지상 7층 | 200 | 1000 | 2100
WD733-그릴창(알루미늄):WD733-그릴창(알루미늄)_600x800mm:2979968:1 | 지상 7층 | 200 | 600 | 800
WD733-그릴창(알루미늄):WD733-그릴창(알루미늄)_600x800mm:2979969:1 | 지상 7층 | 200 | 600 | 800
WD842-2단 하부 더블 프로젝트 창(스테인리스 스틸):WD842-2단 하부 더블 프로젝트 창(스테인리스 스틸)_2000x1800mm:5433400:1 | 지상 7층 | 200 | 2000 | 1800
DR872-샤프트 점검구(스테인리스 스틸):DR872-샤프트 점검구(스테인리스 스틸)_650x1600:3648539:1 | 지상 7층 | 200 | 650 | 1600
DR121-쌍여닫이문(철재, 방화문):DR121-쌍여닫이문(철재, 방화문) 1800x2100mm:3081941:1 | 지상 7층 | 200 | 1800 | 2100
DR872-샤프트 점검구(스테인리스 스틸):DR872-샤프트 점검구(스테인리스 스틸)_650x600:3648540:1 | 지상 7층 | 200 | 650 | 600
DR872-샤프트 점검구(스테인리스 스틸):DR872-샤프트 점검구(스테인리스 스틸)_650x600:3081394:1 | 지상 7층 | 200 | 650 | 600
DR111-외여닫이문(철재,일반)_유리포함(원형):DR111-외여닫이문(철재, 일반)_유리포함 (원형)_2100x1000:3171782:1 | 지상 7층 | 200 | 1000 | 2100
DR111-외여닫이문(철재, 일반, 양개):DR111-외여닫이문(유리, 일반, 양개) 925x1970mm 2:7695868:1 | 지상 7층 | 200 | 925 | 1970
WD842-2단 하부 더블 프로젝트 창(스테인리스 스틸):WD842-2단 하부 더블 프로젝트 창(스테인리스 스틸)_2000x1800mm:5411088:1 | 지상 7층 | 200 | 2000 | 1800
WD812-미들창(스테인리스 스틸):WD812-미들창(스테인리스 스틸) 하부개폐 1000x1600mm:5438290:1 | 지상 8층 | 200 | 1000 | 1600
WD812-미들창(스테인리스 스틸):WD812-미들창(스테인리스 스틸) 하부개폐 800x1200mm:5458605:1 | 지상 8층 | 200 | 800 | 1200
EE111-엘리베이터문(문):EE111-엘리베이터문(20인승)_1100x2550:3839391:1 | 지상 8층 | 200 | 1100 | 2550
EE111-엘리베이터문(문):EE111-엘리베이터문(20인승)_1100x2550:3839390:1 | 지상 8층 | 200 | 1100 | 2550
DR111-외여닫이문(철재,일반)_유리포함(원형):DR111-외여닫이문(철재, 일반)_유리포함 (원형)_2100x1000:3171790:1 | 지상 8층 | 200 | 1000 | 2100
WD733-그릴창(알루미늄):WD733-그릴창(알루미늄)_600x800mm:2980060:1 | 지상 8층 | 200 | 600 | 800
WD733-그릴창(알루미늄):WD733-그릴창(알루미늄)_600x800mm:2980061:1 | 지상 8층 | 200 | 600 | 800
WD842-2단 하부 더블 프로젝트 창(스테인리스 스틸):WD842-2단 하부 더블 프로젝트 창(스테인리스 스틸)_2000x1800mm:5433402:1 | 지상 8층 | 200 | 2000 | 1800
DR872-샤프트 점검구(스테인리스 스틸):DR872-샤프트 점검구(스테인리스 스틸)_650x1600:3648552:1 | 지상 8층 | 200 | 650 | 1600
DR121-쌍여닫이문(철재, 방화문):DR121-쌍여닫이문(철재, 방화문) 1800x2100mm:3081947:1 | 지상 8층 | 200 | 1800 | 2100
DR872-샤프트 점검구(스테인리스 스틸):DR872-샤프트 점검구(스테인리스 스틸)_650x600:3648553:1 | 지상 8층 | 200 | 650 | 600
DR872-샤프트 점검구(스테인리스 스틸):DR872-샤프트 점검구(스테인리스 스틸)_650x600:3081402:1 | 지상 8층 | 200 | 650 | 600
DR111-외여닫이문(철재,일반)_유리포함(원형):DR111-외여닫이문(철재, 일반)_유리포함 (원형)_2100x1000:3171791:1 | 지상 8층 | 200 | 1000 | 2100
DR111-외여닫이문(철재, 일반, 양개):DR111-외여닫이문(유리, 일반, 양개) 925x1970mm 2:7695871:1 | 지상 8층 | 200 | 925 | 1970
WD842-2단 하부 더블 프로젝트 창(스테인리스 스틸):WD842-2단 하부 더블 프로젝트 창(스테인리스 스틸)_2000x1800mm:5411094:1 | 지상 8층 | 200 | 2000 | 1800
WD812-미들창(스테인리스 스틸):WD812-미들창(스테인리스 스틸) 하부개폐 1000x1600mm:5458793:1 | 지상 9층 | 200 | 1000 | 1600
WD812-미들창(스테인리스 스틸):WD812-미들창(스테인리스 스틸) 하부개폐 800x1200mm:5458607:1 | 지상 9층 | 200 | 800 | 1200
DR111-외여닫이문(철재, 일반):DR111-외여닫이문(철재, 일반) 900x2100mm:3081654:1 | 지상 9층 | 200 | 900 | 2100
DR111-외여닫이문(철재, 일반):DR111-외여닫이문(철재, 일반) 1100x2100mm 2:3158142:1 | 지상 9층 | 200 | 1100 | 2100
DR872-샤프트 점검구(스테인리스 스틸):DR872-샤프트 점검구(스테인리스 스틸)_650x1600:3648564:1 | 지상 9층 | 200 | 650 | 1600
EE111-엘리베이터문(문):EE111-엘리베이터문(20인승)_1100x2550:3839433:1 | 지상 9층 | 200 | 1100 | 2550
EE111-엘리베이터문(문):EE111-엘리베이터문(20인승)_1100x2550:3839432:1 | 지상 9층 | 200 | 1100 | 2550
WD733-그릴창(알루미늄):WD733-그릴창(알루미늄)_600x800mm:2980152:1 | 지상 9층 | 200 | 600 | 800
WD733-그릴창(알루미늄):WD733-그릴창(알루미늄)_600x800mm:2980153:1 | 지상 9층 | 200 | 600 | 800
WD842-2단 하부 더블 프로젝트 창(스테인리스 스틸):WD842-2단 하부 더블 프로젝트 창(스테인리스 스틸)_2000x1800mm:5433404:1 | 지상 9층 | 200 | 2000 | 1800
DR872-샤프트 점검구(스테인리스 스틸):DR872-샤프트 점검구(스테인리스 스틸)_650x1600:3648565:1 | 지상 9층 | 200 | 650 | 1600
DR121-쌍여닫이문(철재, 방화문):DR121-쌍여닫이문(철재, 방화문) 1800x2100mm:3081953:1 | 지상 9층 | 200 | 1800 | 2100
DR872-샤프트 점검구(스테인리스 스틸):DR872-샤프트 점검구(스테인리스 스틸)_650x600:3648566:1 | 지상 9층 | 200 | 650 | 600
DR872-샤프트 점검구(스테인리스 스틸):DR872-샤프트 점검구(스테인리스 스틸)_650x600:3081410:1 | 지상 9층 | 200 | 650 | 600
DR111-외여닫이문(철재,일반)_유리포함(원형):DR111-외여닫이문(철재, 일반)_유리포함 (원형)_2100x1000:3171800:1 | 지상 9층 | 200 | 1000 | 2100
DR111-외여닫이문(철재, 일반, 양개):DR111-외여닫이문(유리, 일반, 양개) 925x1970mm 2:7695874:1 | 지상 9층 | 200 | 925 | 1970
WD842-2단 하부 더블 프로젝트 창(스테인리스 스틸):WD842-2단 하부 더블 프로젝트 창(스테인리스 스틸)_2000x1800mm:5411100:1 | 지상 9층 | 200 | 2000 | 1800
WD812-미들창(스테인리스 스틸):WD812-미들창(스테인리스 스틸) 하부개폐 1000x1600mm:5458810:1 | 지상 10층 | 368 | 1000 | 1600
WD733-그릴창(알루미늄):WD733-그릴창(알루미늄)_600x800mm:2980244:1 | 지상 10층 | 236 | 600 | 800
WD733-그릴창(알루미늄):WD733-그릴창(알루미늄)_600x800mm:2980245:1 | 지상 10층 | 236 | 600 | 800
DR872-샤프트 점검구(스테인리스 스틸):DR872-샤프트 점검구(스테인리스 스틸)_650x600:3081418:1 | 지상 10층 | 248 | 650 | 600
DR111-외여닫이문(철재, 일반, 양개):DR111-외여닫이문(유리, 일반, 양개) 925x1970mm 2:7695877:1 | 지상 10층 | 298 | 925 | 1970
WD842-2단 하부 더블 프로젝트 창(스테인리스 스틸):WD842-2단 하부 더블 프로젝트 창(스테인리스 스틸)_2000x1800mm:5411236:1 | 지상 10층 | 368 | 2000 | 1800
DR111-외여닫이문(철재, 일반):DR111-외여닫이문(철재, 일반) 1100x2100mm 2:3158435:1 | 옥탑층 | 200 | 1100 | 2100
DR111-외여닫이문(철재, 일반):DR111-외여닫이문(철재, 일반) 900x2100mm:3158476:1 | 옥탑층 | 200 | 900 | 2100
WD812-미들창(스테인리스 스틸):WD812-미들창(스테인리스 스틸) 하부개폐 1000x1600mm:5458852:1 | 옥탑층 | 200 | 1000 | 1600
WD812-미들창(스테인리스 스틸):WD812-미들창(스테인리스 스틸) 하부개폐 800x1200mm:5458870:1 | 옥탑층 | 200 | 800 | 1200
WD812-미들창(스테인리스 스틸):WD812-미들창(스테인리스 스틸) 하부개폐 1000x1600mm:5458861:1 | 옥탑층 | 200 | 1000 | 1600
DR422-회전문(전동식, 스테인리스 스틸):DR422-회전문(전동식, 스테인리스 스틸) 3000x2400mm:7363509:1 | 지상 1층 | 80 | 3000 | 2400
DR222-외미닫이 자동문(전동식) 2000X2600mm:DR222-외미닫이 자동문(전동식) 2000X2600mm:7363617:1 | 지상 1층 | 80 | 2090 | 2600
DR111-외여닫이문(철재, 일반, 양개):DR111-외여닫이문(유리, 일반, 양개) 950x2100mm:7686514:1 | 지상 1층 | 100 | 950 | 2100
DR111-외여닫이문(철재, 일반):DR111-외여닫이문(철재, 일반) 1100x2100mm 2:3043795:1 | 지하2층 | 200 | 1100 | 2100
DR121-쌍여닫이문(철재, 방화문):DR121-쌍여닫이문(철재, 방화문) 1800x2100mm:3047872:1 | 지하2층 | 200 | 1800 | 2100
DR121-쌍여닫이문(철재, 방화문):DR121-쌍여닫이문(철재, 방화문) 1800x2100mm:3054797:1 | 지하1층 | 200 | 1800 | 2100
DR121-쌍여닫이문(철재, 방화문):DR121-쌍여닫이문(철재, 방화문) 1800x2100mm:3054927:1 | 지하1층 | 200 | 1800 | 2100
DR872-샤프트 점검구(스테인리스 스틸):DR872-샤프트 점검구(스테인리스 스틸)_650x1600:3055070:1 | 지상 3층 | 200 | 650 | 1600
DR872-샤프트 점검구(스테인리스 스틸):DR872-샤프트 점검구(스테인리스 스틸)_650x1600:3055071:1 | 지상 3층 | 200 | 650 | 1600
DR111-외여닫이문(철재, 일반):DR111-외여닫이문(철재, 일반) 900x2100mm:3081618:1 | 지상 3층 | 200 | 900 | 2100
DR111-외여닫이문(철재, 일반):DR111-외여닫이문(철재, 일반) 900x2100mm:3081630:1 | 지상 5층 | 200 | 900 | 2100
DR111-외여닫이문(철재, 일반):DR111-외여닫이문(철재, 일반) 900x2100mm:3081636:1 | 지상 6층 | 200 | 900 | 2100
DR111-외여닫이문(철재, 일반):DR111-외여닫이문(철재, 일반) 900x2100mm:3081648:1 | 지상 8층 | 200 | 900 | 2100
DR111-외여닫이문(철재, 일반):DR111-외여닫이문(철재, 일반) 900x2100mm:3081660:1 | 지상 10층 | 236 | 900 | 2100
DR121-쌍여닫이문(철재, 방화문):DR121-쌍여닫이문(철재, 방화문) 1800x2100mm:3081917:1 | 지상 3층 | 200 | 1800 | 2100
DR121-쌍여닫이문(철재, 방화문):DR121-쌍여닫이문(철재, 방화문) 1800x2100mm:3081959:1 | 지상 10층 | 236 | 1800 | 2100
DR121-쌍여닫이문(철재, 방화문):DR121-쌍여닫이문(철재, 방화문) 1800x2100mm:3094399:1 | 옥탑층 | 200 | 1800 | 2100
DR111-외여닫이문(철재, 일반):DR111-외여닫이문(철재, 일반) 1100x2100mm 2:3094450:1 | 옥탑층 | 200 | 1100 | 2100
WD733-그릴창(알루미늄):WD733-그릴창(알루미늄)_600x800mm:3190889:1 | 지상 1층 | 200 | 600 | 800
WD733-그릴창(알루미늄):WD733-그릴창(알루미늄)_600x800mm:3190927:1 | 지상 1층 | 200 | 600 | 800
DR111-외여닫이문(철재, 일반):DR111-외여닫이문(철재, 일반) 1100x2100mm 2:3158112:1 | 지상 3층 | 200 | 1100 | 2100
DR111-외여닫이문(철재, 일반):DR111-외여닫이문(철재, 일반) 1100x2100mm 2:3158122:1 | 지상 5층 | 200 | 1100 | 2100
DR111-외여닫이문(철재, 일반):DR111-외여닫이문(철재, 일반) 1100x2100mm 2:3158127:1 | 지상 6층 | 200 | 1100 | 2100
DR111-외여닫이문(철재, 일반):DR111-외여닫이문(철재, 일반) 1100x2100mm 2:3158137:1 | 지상 8층 | 200 | 1100 | 2100
DR111-외여닫이문(철재, 일반):DR111-외여닫이문(철재, 일반) 1100x2100mm 2:3158147:1 | 지상 10층 | 236 | 1100 | 2100
DR111-외여닫이문(철재,일반)_유리포함(원형):DR111-외여닫이문(철재, 일반)_유리포함 (원형)_2100x1000:3171736:1 | 지상 1층 | 200 | 1000 | 2100
DR111-외여닫이문(철재,일반)_유리포함(원형):DR111-외여닫이문(철재, 일반)_유리포함 (원형)_2100x1000:3171754:1 | 지상 4층 | 200 | 1000 | 2100
DR111-외여닫이문(철재,일반)_유리포함(원형):DR111-외여닫이문(철재, 일반)_유리포함 (원형)_2100x1000:3171772:1 | 지상 6층 | 200 | 1000 | 2100
DR111-외여닫이문(철재,일반)_유리포함(원형):DR111-외여닫이문(철재, 일반)_유리포함 (원형)_2100x1000:3171799:1 | 지상 9층 | 200 | 1000 | 2100
DR111-외여닫이문(철재,일반)_유리포함(원형):DR111-외여닫이문(철재, 일반)_유리포함 (원형)_2100x1000:3171808:1 | 지상 10층 | 248 | 1000 | 2100
DR111-외여닫이문(철재,일반)_유리포함(원형):DR111-외여닫이문(철재, 일반)_유리포함 (원형)_2100x1000:3171809:1 | 지상 10층 | 248 | 1000 | 2100
DR111-외여닫이문(철재, 일반):DR111-외여닫이문(철재, 일반) 900x2100mm:3173908:1 | 지하2층 | 200 | 900 | 2100
DR872-샤프트 점검구(스테인리스 스틸):DR872-샤프트 점검구(스테인리스 스틸)_650x1600:3648512:1 | 지상 5층 | 200 | 650 | 1600
DR872-샤프트 점검구(스테인리스 스틸):DR872-샤프트 점검구(스테인리스 스틸)_650x1600:3648525:1 | 지상 6층 | 200 | 650 | 1600
DR872-샤프트 점검구(스테인리스 스틸):DR872-샤프트 점검구(스테인리스 스틸)_650x1600:3648551:1 | 지상 8층 | 200 | 650 | 1600
DR872-샤프트 점검구(스테인리스 스틸):DR872-샤프트 점검구(스테인리스 스틸)_650x1600:3648577:1 | 지상 10층 | 236 | 650 | 1600
DR872-샤프트 점검구(스테인리스 스틸):DR872-샤프트 점검구(스테인리스 스틸)_650x1600:3648578:1 | 지상 10층 | 236 | 650 | 1600
DR872-샤프트 점검구(스테인리스 스틸):DR872-샤프트 점검구(스테인리스 스틸)_650x600:3648579:1 | 지상 10층 | 236 | 650 | 600
EE111-엘리베이터문(문):EE111-엘리베이터문(13인승)_1100x2550:3838408:1 | 지상 1층 | 200 | 1100 | 2550
EE111-엘리베이터문(문):EE111-엘리베이터문(20인승)_1100x2550:3839180:1 | 지상 3층 | 200 | 1100 | 2550
EE111-엘리베이터문(문):EE111-엘리베이터문(20인승)_1100x2550:3839181:1 | 지상 3층 | 200 | 1100 | 2550
EE111-엘리베이터문(문):EE111-엘리베이터문(20인승)_1100x2550:3839474:1 | 지상 10층 | 236 | 1100 | 2550
EE111-엘리베이터문(문):EE111-엘리베이터문(20인승)_1100x2550:3839475:1 | 지상 10층 | 236 | 1100 | 2550
EE111-엘리베이터문(문):EE111-엘리베이터문(13인승)_1100x2550:3839515:1 | 지하1층 | 200 | 1100 | 2550
EE111-엘리베이터문(문):EE111-엘리베이터문(20인승)_1100x2550:3839516:1 | 지하1층 | 200 | 1100 | 2550
EE111-엘리베이터문(문):EE111-엘리베이터문(20인승)_1100x2550:3839517:1 | 지하1층 | 200 | 1100 | 2550
EE111-엘리베이터문(문):EE111-엘리베이터문(13인승)_1100x2550:3839557:1 | 지하2층 | 200 | 1100 | 2550
EE111-엘리베이터문(문):EE111-엘리베이터문(20인승)_1100x2550:3839558:1 | 지하2층 | 200 | 1100 | 2550
EE111-엘리베이터문(문):EE111-엘리베이터문(20인승)_1100x2550:3839559:1 | 지하2층 | 200 | 1100 | 2550
DR111-외여닫이문(철재, 일반):DR111-외여닫이문(철재, 일반) 900x2100mm:5903200:1 | 지상 3층 | 200 | 900 | 2100
DR111-외여닫이문(철재, 일반):DR111-외여닫이문(철재, 일반) 900x2100mm:5326951:1 | 지하2층 | 200 | 900 | 2100
DR872-샤프트 점검구(스테인리스 스틸):DR872-샤프트 점검구(스테인리스 스틸)_650x1600:5326964:1 | 지하2층 | 200 | 650 | 1600
DR121-쌍여닫이문(철재, 일반, 양개):DR121-쌍여닫이문(유리, 일반, 양개) 1500x2100mm:7728298:1 | 지상 3층 | 90 | 1500 | 2100
DR121-쌍여닫이문(철재, 일반, 양개):DR121-쌍여닫이문(유리, 일반, 양개) 1500x2100mm:7728299:1 | 지상 3층 | 90 | 1500 | 2100
DR121-쌍여닫이문(철재, 일반, 양개):DR121-쌍여닫이문(유리, 일반, 양개) 1500x2100mm:7698513:1 | 지상 4층 | 90 | 1500 | 2100
DR121-쌍여닫이문(철재, 일반, 양개):DR121-쌍여닫이문(유리, 일반, 양개) 1500x2100mm:7698925:1 | 지상 4층 | 90 | 1500 | 2100
DR121-쌍여닫이문(철재, 일반, 양개):DR121-쌍여닫이문(유리, 일반, 양개) 1500x2100mm:8073673:1 | 지상 4층 | 90 | 1500 | 2100
DR121-쌍여닫이문(철재, 일반, 양개):DR121-쌍여닫이문(유리, 일반, 양개) 1450x2100mm 2:7696411:1 | 지상 5층 | 90 | 1450 | 2100
DR121-쌍여닫이문(철재, 일반, 양개):DR121-쌍여닫이문(유리, 일반, 양개) 1500x2100mm:7698523:1 | 지상 5층 | 90 | 1500 | 2100
DR121-쌍여닫이문(철재, 일반, 양개):DR121-쌍여닫이문(유리, 일반, 양개) 1500x2100mm:7728314:1 | 지상 5층 | 90 | 1500 | 2100
DR121-쌍여닫이문(철재, 일반, 양개):DR121-쌍여닫이문(유리, 일반, 양개) 1500x2100mm:7728315:1 | 지상 5층 | 90 | 1500 | 2100
DR121-쌍여닫이문(철재, 일반, 양개):DR121-쌍여닫이문(유리, 일반, 양개) 1500x2100mm:7698932:1 | 지상 5층 | 90 | 1500 | 2100
DR121-쌍여닫이문(철재, 일반, 양개):DR121-쌍여닫이문(유리, 일반, 양개) 1500x2100mm:7696564:1 | 지상 5층 | 90 | 1500 | 2100
DR121-쌍여닫이문(철재, 일반, 양개):DR121-쌍여닫이문(유리, 일반, 양개) 1450x2100mm 2:7696419:1 | 지상 6층 | 90 | 1450 | 2100
DR121-쌍여닫이문(철재, 일반, 양개):DR121-쌍여닫이문(유리, 일반, 양개) 1500x2100mm:7698529:1 | 지상 6층 | 90 | 1500 | 2100
DR121-쌍여닫이문(철재, 일반, 양개):DR121-쌍여닫이문(유리, 일반, 양개) 1500x2100mm:7728321:1 | 지상 6층 | 90 | 1500 | 2100
DR121-쌍여닫이문(철재, 일반, 양개):DR121-쌍여닫이문(유리, 일반, 양개) 1500x2100mm:7728322:1 | 지상 6층 | 90 | 1500 | 2100
DR121-쌍여닫이문(철재, 일반, 양개):DR121-쌍여닫이문(유리, 일반, 양개) 1500x2100mm:7698935:1 | 지상 6층 | 90 | 1500 | 2100
DR121-쌍여닫이문(철재, 일반, 양개):DR121-쌍여닫이문(유리, 일반, 양개) 1500x2100mm:7696567:1 | 지상 6층 | 90 | 1500 | 2100
DR121-쌍여닫이문(철재, 일반, 양개):DR121-쌍여닫이문(유리, 일반, 양개) 1450x2100mm 2:7696423:1 | 지상 7층 | 90 | 1450 | 2100
DR121-쌍여닫이문(철재, 일반, 양개):DR121-쌍여닫이문(유리, 일반, 양개) 1500x2100mm:7698534:1 | 지상 7층 | 90 | 1500 | 2100
DR121-쌍여닫이문(철재, 일반, 양개):DR121-쌍여닫이문(유리, 일반, 양개) 1500x2100mm:7728328:1 | 지상 7층 | 90 | 1500 | 2100
DR121-쌍여닫이문(철재, 일반, 양개):DR121-쌍여닫이문(유리, 일반, 양개) 1500x2100mm:7728329:1 | 지상 7층 | 90 | 1500 | 2100
DR121-쌍여닫이문(철재, 일반, 양개):DR121-쌍여닫이문(유리, 일반, 양개) 1500x2100mm:7698938:1 | 지상 7층 | 90 | 1500 | 2100
DR121-쌍여닫이문(철재, 일반, 양개):DR121-쌍여닫이문(유리, 일반, 양개) 1500x2100mm:7696570:1 | 지상 7층 | 90 | 1500 | 2100
DR121-쌍여닫이문(철재, 일반, 양개):DR121-쌍여닫이문(유리, 일반, 양개) 1450x2100mm 2:7696426:1 | 지상 8층 | 90 | 1450 | 2100
DR121-쌍여닫이문(철재, 일반, 양개):DR121-쌍여닫이문(유리, 일반, 양개) 1500x2100mm:7698539:1 | 지상 8층 | 90 | 1500 | 2100
DR121-쌍여닫이문(철재, 일반, 양개):DR121-쌍여닫이문(유리, 일반, 양개) 1500x2100mm:7728335:1 | 지상 8층 | 90 | 1500 | 2100
DR121-쌍여닫이문(철재, 일반, 양개):DR121-쌍여닫이문(유리, 일반, 양개) 1500x2100mm:7728336:1 | 지상 8층 | 90 | 1500 | 2100
DR121-쌍여닫이문(철재, 일반, 양개):DR121-쌍여닫이문(유리, 일반, 양개) 1500x2100mm:7698941:1 | 지상 8층 | 90 | 1500 | 2100
DR121-쌍여닫이문(철재, 일반, 양개):DR121-쌍여닫이문(유리, 일반, 양개) 1500x2100mm:7696573:1 | 지상 8층 | 90 | 1500 | 2100
DR121-쌍여닫이문(철재, 일반, 양개):DR121-쌍여닫이문(유리, 일반, 양개) 1500x2100mm:7698546:1 | 지상 9층 | 90 | 1500 | 2100
DR121-쌍여닫이문(철재, 일반, 양개):DR121-쌍여닫이문(유리, 일반, 양개) 1500x2100mm:7728343:1 | 지상 9층 | 90 | 1500 | 2100
DR121-쌍여닫이문(철재, 일반, 양개):DR121-쌍여닫이문(유리, 일반, 양개) 1500x2100mm:7728344:1 | 지상 9층 | 90 | 1500 | 2100
DR121-쌍여닫이문(철재, 일반, 양개):DR121-쌍여닫이문(유리, 일반, 양개) 1500x2100mm:8073327:1 | 지상 9층 | 90 | 1500 | 2100
DR121-쌍여닫이문(철재, 일반, 양개):DR121-쌍여닫이문(유리, 일반, 양개) 1500x2100mm:7696576:1 | 지상 9층 | 90 | 1500 | 2100
DR121-쌍여닫이문(철재, 일반, 양개):DR121-쌍여닫이문(유리, 일반, 양개) 1500x2100mm:7698552:1 | 지상 10층 | 126 | 1500 | 2100
DR121-쌍여닫이문(철재, 일반, 양개):DR121-쌍여닫이문(유리, 일반, 양개) 1500x2100mm:7698553:1 | 지상 10층 | 126 | 1500 | 2100
DR121-쌍여닫이문(철재, 일반, 양개):DR121-쌍여닫이문(유리, 일반, 양개) 1500x2100mm:7728350:1 | 지상 10층 | 126 | 1500 | 2100
DR121-쌍여닫이문(철재, 일반, 양개):DR121-쌍여닫이문(유리, 일반, 양개) 1500x2100mm:7728351:1 | 지상 10층 | 126 | 1500 | 2100
DR121-쌍여닫이문(철재, 일반, 양개):DR121-쌍여닫이문(유리, 일반, 양개) 1500x2100mm:7698947:1 | 지상 10층 | 126 | 1500 | 2100
DR121-쌍여닫이문(철재, 일반, 양개):DR121-쌍여닫이문(유리, 일반, 양개) 1500x2100mm:7696579:1 | 지상 10층 | 126 | 1500 | 2100
DR121-쌍여닫이문(철재, 일반, 양개):DR121-쌍여닫이문(유리, 일반, 양개) 1500x2100mm:7698547:1 | 지상 9층 | 90 | 1500 | 2100
DR121-쌍여닫이문(철재, 일반, 양개):DR121-쌍여닫이문(유리, 일반, 양개) 1500x2100mm:7698514:1 | 지상 4층 | 90 | 1500 | 2100
DR121-쌍여닫이문(철재, 일반, 양개):DR121-쌍여닫이문(유리, 일반, 양개) 1500x2100mm:7698524:1 | 지상 5층 | 90 | 1500 | 2100
DR121-쌍여닫이문(철재, 일반, 양개):DR121-쌍여닫이문(유리, 일반, 양개) 1500x2100mm:7698530:1 | 지상 6층 | 90 | 1500 | 2100
DR121-쌍여닫이문(철재, 일반, 양개):DR121-쌍여닫이문(유리, 일반, 양개) 1500x2100mm:7698535:1 | 지상 7층 | 90 | 1500 | 2100
DR121-쌍여닫이문(철재, 일반, 양개):DR121-쌍여닫이문(유리, 일반, 양개) 1500x2100mm:7698540:1 | 지상 8층 | 90 | 1500 | 2100
WD842-2단 하부 더블 프로젝트 창(스테인리스 스틸):WD842-2단 하부 더블 프로젝트 창(스테인리스 스틸)_2000x1800mm:5433406:1 | 지상 10층 | 368 | 2000 | 1800
WD842-2단 하부 더블 프로젝트 창(스테인리스 스틸):WD842-2단 하부 더블 프로젝트 창(스테인리스 스틸)_1500x1600mm:5433475:1 | 지상 4층 | 200 | 1500 | 1600
WD842-2단 하부 더블 프로젝트 창(스테인리스 스틸):WD842-2단 하부 더블 프로젝트 창(스테인리스 스틸)_1500x1600mm:5433523:1 | 지상 1층 | 200 | 1500 | 1600
WD842-2단 하부 더블 프로젝트 창(스테인리스 스틸):WD842-2단 하부 더블 프로젝트 창(스테인리스 스틸)_1500x1600mm:5433525:1 | 지상 2층 | 200 | 1500 | 1600
WD842-2단 하부 더블 프로젝트 창(스테인리스 스틸):WD842-2단 하부 더블 프로젝트 창(스테인리스 스틸)_1500x1600mm:5433527:1 | 지상 3층 | 200 | 1500 | 1600
WD842-2단 하부 더블 프로젝트 창(스테인리스 스틸):WD842-2단 하부 더블 프로젝트 창(스테인리스 스틸)_1500x1600mm:5433529:1 | 지상 5층 | 200 | 1500 | 1600
WD842-2단 하부 더블 프로젝트 창(스테인리스 스틸):WD842-2단 하부 더블 프로젝트 창(스테인리스 스틸)_1500x1600mm:5433531:1 | 지상 6층 | 200 | 1500 | 1600
WD842-2단 하부 더블 프로젝트 창(스테인리스 스틸):WD842-2단 하부 더블 프로젝트 창(스테인리스 스틸)_1500x1600mm:5433533:1 | 지상 7층 | 200 | 1500 | 1600
WD842-2단 하부 더블 프로젝트 창(스테인리스 스틸):WD842-2단 하부 더블 프로젝트 창(스테인리스 스틸)_1500x1600mm:5433535:1 | 지상 8층 | 200 | 1500 | 1600
WD842-2단 하부 더블 프로젝트 창(스테인리스 스틸):WD842-2단 하부 더블 프로젝트 창(스테인리스 스틸)_1500x1600mm:5433537:1 | 지상 9층 | 200 | 1500 | 1600
WD842-2단 하부 더블 프로젝트 창(스테인리스 스틸):WD842-2단 하부 더블 프로젝트 창(스테인리스 스틸)_1500x1600mm:5433539:1 | 지상 10층 | 368 | 1500 | 1600
WD812-미들창(스테인리스 스틸):WD812-미들창(스테인리스 스틸) 하부개폐 800x1200mm:5458593:1 | 지상 1층 | 200 | 800 | 1200
WD812-미들창(스테인리스 스틸):WD812-미들창(스테인리스 스틸) 하부개폐 800x1200mm:5458609:1 | 지상 10층 | 380 | 800 | 1200
WD812-미들창(스테인리스 스틸):WD812-미들창(스테인리스 스틸) 하부개폐 1000x1600mm:5458777:1 | 지상 1층 | 200 | 1000 | 1600
WD812-미들창(스테인리스 스틸):WD812-미들창(스테인리스 스틸) 하부개폐 1000x1600mm:5458824:1 | 옥탑층 | 200 | 1000 | 1600
WD812-미들창(스테인리스 스틸):WD812-미들창(스테인리스 스틸) 하부개폐 1000x1600mm:5458834:1 | 옥탑층 | 200 | 1000 | 1600
DR111-외여닫이문(철재, 일반):DR111-외여닫이문(철재, 일반) 1100x2100mm 2:5862534:1 | 지상 1층 | 200 | 1100 | 2100
DR111-외여닫이문(철재, 일반):DR111-외여닫이문(철재, 일반) 900x2100mm:5863220:1 | 지상 1층 | 200 | 900 | 2100
DR111-외여닫이문(철재, 일반, 양개):DR111-외여닫이문(유리, 일반, 양개) 950x2100mm:5903316:1 | 지상 2층 | 200 | 950 | 2100
DR111-외여닫이문(철재, 일반):DR111-외여닫이문(철재, 일반) 900x2100mm:5903320:1 | 지상 9층 | 200 | 900 | 2100
DR111-외여닫이문(철재, 일반):DR111-외여닫이문(철재, 일반) 900x2100mm:5903324:1 | 지상 10층 | 236 | 900 | 2100
DR121-쌍여닫이문(철재, 일반, 양개):DR121-쌍여닫이문(유리, 일반, 양개) 1500x2100mm:8073623:1 | 지상 9층 | 90 | 1500 | 2100
DR121-쌍여닫이문(철재, 일반, 양개):DR121-쌍여닫이문(유리, 일반, 양개) 1500x2100mm:8073629:1 | 지상 10층 | 126 | 1500 | 2100
EE111-엘리베이터문(문):EE111-엘리베이터문(13인승)_1100x2550:6568631:1 | 지상 2층 | 200 | 1100 | 2550
EE111-엘리베이터문(문):EE111-엘리베이터문(13인승)_1100x2550:6568636:1 | 지상 3층 | 200 | 1100 | 2550
EE111-엘리베이터문(문):EE111-엘리베이터문(13인승)_1100x2550:6568641:1 | 지상 4층 | 200 | 1100 | 2550
EE111-엘리베이터문(문):EE111-엘리베이터문(13인승)_1100x2550:6568646:1 | 지상 5층 | 200 | 1100 | 2550
EE111-엘리베이터문(문):EE111-엘리베이터문(13인승)_1100x2550:6568651:1 | 지상 6층 | 200 | 1100 | 2550
EE111-엘리베이터문(문):EE111-엘리베이터문(13인승)_1100x2550:6568656:1 | 지상 7층 | 200 | 1100 | 2550
EE111-엘리베이터문(문):EE111-엘리베이터문(13인승)_1100x2550:6568661:1 | 지상 8층 | 200 | 1100 | 2550
EE111-엘리베이터문(문):EE111-엘리베이터문(13인승)_1100x2550:6568666:1 | 지상 9층 | 200 | 1100 | 2550
EE111-엘리베이터문(문):EE111-엘리베이터문(13인승)_1100x2550:6568671:1 | 지상 10층 | 236 | 1100 | 2550
DR120-쌍여닫이문:DR120-쌍여닫이문:7678817:1 | 지상 1층 | 100 | 1750 | 2100
DR111-외여닫이문(철재, 일반, 양개):DR111-외여닫이문(유리, 일반, 양개) 950x2100mm:7685884:1 | 지상 1층 | 100 | 950 | 2100
DR111-외여닫이문(철재, 일반, 양개):DR111-외여닫이문(유리, 일반, 양개) 950x2100mm:7686033:1 | 지상 1층 | 100 | 950 | 2100
DR111-외여닫이문(철재, 일반, 양개):DR111-외여닫이문(유리, 일반, 양개) 950x2100mm:7686843:1 | 지상 1층 | 100 | 950 | 2100
DR111-외여닫이문(철재, 일반, 양개):DR111-외여닫이문(유리, 일반, 양개) 950x2100mm:7687529:1 | 지상 1층 | 100 | 950 | 2100
DR120-쌍여닫이문:DR120-쌍여닫이문:7687815:1 | 지상 1층 | 100 | 1750 | 2100
DR120-쌍여닫이문:DR120-쌍여닫이문:7687873:1 | 지상 1층 | 100 | 1750 | 2100
DR111-외여닫이문(철재, 일반, 양개):DR111-외여닫이문(유리, 일반, 양개) 950x2100mm:7688146:1 | 지상 1층 | 100 | 950 | 2100
DR111-외여닫이문(철재, 일반, 양개):DR111-외여닫이문(유리, 일반, 양개) 950x2100mm:7688226:1 | 지상 1층 | 100 | 950 | 2100
DR111-외여닫이문(철재, 일반, 양개):DR111-외여닫이문(유리, 일반, 양개) 950x2100mm:7688318:1 | 지상 1층 | 100 | 950 | 2100
DR111-외여닫이문(철재, 일반, 양개):DR111-외여닫이문(유리, 일반, 양개) 950x2100mm:7688368:1 | 지상 1층 | 100 | 950 | 2100
DR111-외여닫이문(철재, 일반, 양개):DR111-외여닫이문(유리, 일반, 양개) 950x2100mm:7689790:1 | 지상 1층 | 100 | 950 | 2100
DR121-쌍여닫이문(철재, 일반, 양개):DR121-쌍여닫이문(유리, 일반, 양개) 1500x2100mm:7693272:1 | 지상 2층 | 100 | 1500 | 2100
DR121-쌍여닫이문(철재, 일반, 양개):DR121-쌍여닫이문(유리, 일반, 양개) 1450x2100mm 2:7696018:1 | 지상 4층 | 100 | 1450 | 2100
DR121-쌍여닫이문(철재, 일반, 양개):DR121-쌍여닫이문(유리, 일반, 양개) 1500x2100mm:7697924:1 | 지상 3층 | 100 | 1500 | 2100
WD812-미들창(스테인리스 스틸):WD812-미들창(스테인리스 스틸) 하부개폐 1000x1600mm:8084605:1 | 옥탑층 | 200 | 1000 | 1600

# IfcPlate: CW300-THK24.Low-e coating glass:CW300-THK24.Low-e coating glass (2337)
Type - PredefinedType: CURTAIN_PANEL; Material: KBIMS-로이유리(코팅)
Type - ID 데이터 - OmniClass 번호: 23.25.20.14.11.11.17; OmniClass 제목: Infill Panels; 유형 이름: CW300-THK24.Low-e coating glass
Type - 기타 - 카테고리: 커튼월 패널; KBIMS-부위코드: E336; 제작정보: bSK-2021_KBIMS2.0-bC; 조달청표준공사코드: ALC1; 패밀리 이름: CW300-THK24.Low-e coating glass
Type - 재료 및 마감재 - 유리 재료: KBIMS-로이유리(코팅)
Type - 치수 - A: 0 mm; B: 0 mm; 유리 두께: 24 mm; 중심이동: 0 mm
Type - 해석 특성 - 열 특성 정의 기준: 개략적 유형; 해석 시공: <없음>
Type - Pset_PlateCommon - IsExternal: no
공정 - 생성 공정: 새 구성
기타 - 유형: CW300-THK24.Low-e coating glass; 유형 ID: 6832454; 패밀리: CW300-THK24.Low-e coating glass; 패밀리 및 유형: CW300-THK24.Low-e coating glass: CW300-THK24.Low-e coating glass
Pset_PlateCommon - Reference: CW300-THK24.Low-e coating glass
Pset_QuantityTakeOff - Reference: CW300-THK24.Low-e coating glass
Name (CW300-THK24.Low-e coating glass:CW300-THK24.Low-e coating glass:...) | In | 레벨 | 호스트 ID | 높이 (mm) | 면적 (m2) | 체적 (m3) = NetVolume (m3) | 폭 (mm)
2836337 | 지상 1층 | 지상 1층 | 2836336 | 2025 | 2.37944 | 0.0571067 | 1175.03
2836869 | 지상 1층 | 지상 1층 | 2836336 | 2025 | 2.2275 | 0.05346 | 1100
2837031 | 지상 1층 | 지상 1층 | 2836336 | 2025 | 2.53125 | 0.06075 | 1250
2837252 | 지상 1층 | 지상 1층 | 2836336 | 2025 | 2.93618 | 0.0704683 | 1449.97
2837113 | 지상 1층 | 지상 1층 | 2836336 | 1345 | 1.58042 | 0.0379301 | 1175.03
2837114 | 지상 1층 | 지상 1층 | 2836336 | 1345 | 1.4795 | 0.035508 | 1100
2837115 | 지상 1층 | 지상 1층 | 2836336 | 1345 | 1.27775 | 0.030666 | 950
2837116 | 지상 1층 | 지상 1층 | 2836336 | 1345 | 1.68125 | 0.04035 | 1250
2837253 | 지상 1층 | 지상 1층 | 2836336 | 1345 | 1.9502 | 0.0468049 | 1449.97
2837365 | 지상 1층 | 지상 1층 | 2836336 | 1345 | 1.24415 | 0.0298596 | 925.017
2838632 | 지상 1층 | 지상 1층 | 2838631 | 2025 | 2.37941 | 0.0571058 | 1175.02
2838638 | 지상 1층 | 지상 1층 | 2838631 | 2025 | 2.2275 | 0.05346 | 1100
2838648 | 지상 1층 | 지상 1층 | 2838631 | 2025 | 1.97438 | 0.047385 | 975
2838667 | 지상 1층 | 지상 1층 | 2838631 | 2025 | 1.97438 | 0.047385 | 975
2838653 | 지상 1층 | 지상 1층 | 2838631 | 1345 | 1.5804 | 0.0379296 | 1175.02
2838654 | 지상 1층 | 지상 1층 | 2838631 | 1345 | 1.4795 | 0.035508 | 1100
2838655 | 지상 1층 | 지상 1층 | 2838631 | 1345 | 1.27775 | 0.030666 | 950
2838656 | 지상 1층 | 지상 1층 | 2838631 | 1345 | 1.31138 | 0.031473 | 975
2838668 | 지상 1층 | 지상 1층 | 2838631 | 1345 | 1.31138 | 0.031473 | 975
2838676 | 지상 1층 | 지상 1층 | 2838631 | 1345 | 1.44585 | 0.0347004 | 1074.98
2839600 | 지상 1층 | 지상 1층 | 2839308 | 2025 | 2.268 | 0.054432 | 1120
2839803 | 지상 1층 | 지상 1층 | 2839308 | 2025 | 2.268 | 0.054432 | 1120
2839320 | 지상 1층 | 지상 1층 | 2839308 | 2025 | 3.0375 | 0.0729 | 1500 | ID 데이터 - 마크: 48
2839325 | 지상 1층 | 지상 1층 | 2839308 | 2025 | 3.0375 | 0.0729 | 1500
2839352 | 지상 1층 | 지상 1층 | 2839308 | 2025 | 4.60681 | 0.110563 | 2274.97 | ID 데이터 - 마크: 49
2839330 | 지상 1층 | 지상 1층 | 2839308 | 1345 | 1.37865 | 0.0330876 | 1025.02
2839601 | 지상 1층 | 지상 1층 | 2839308 | 1345 | 1.5064 | 0.0361536 | 1120
2839804 | 지상 1층 | 지상 1층 | 2839308 | 1345 | 1.5064 | 0.0361536 | 1120
2839331 | 지상 1층 | 지상 1층 | 2839308 | 1345 | 1.2912 | 0.0309888 | 960
2839332 | 지상 1층 | 지상 1층 | 2839308 | 1345 | 2.0175 | 0.04842 | 1500
2839333 | 지상 1층 | 지상 1층 | 2839308 | 1345 | 2.0175 | 0.04842 | 1500
2839345 | 지상 1층 | 지상 1층 | 2839308 | 1345 | 1.27775 | 0.030666 | 950
2839353 | 지상 1층 | 지상 1층 | 2839308 | 1345 | 3.05983 | 0.0734359 | 2274.97
2842072 | 지상 1층 | 지상 1층 | 2842071 | 1925 | 3.33178 | 0.0799626 | 1730.79
2842778 | 지상 1층 | 지상 1층 | 2842071 | 1925 | 3.08 | 0.07392 | 1600
2842498 | 지상 1층 | 지상 1층 | 2842071 | 1925 | 3.08 | 0.07392 | 1600
2842898 | 지상 1층 | 지상 1층 | 2842071 | 1925 | 3.08 | 0.07392 | 1600
2843038 | 지상 1층 | 지상 1층 | 2842071 | 1925 | 3.08 | 0.07392 | 1600
2843112 | 지상 1층 | 지상 1층 | 2842071 | 1925 | 3.08 | 0.07392 | 1600
2843229 | 지상 1층 | 지상 1층 | 2842071 | 1925 | 3.40572 | 0.0817374 | 1769.21
2842679 | 지상 1층 | 지상 1층 | 2842071 | 1445 | 2.501 | 0.0600239 | 1730.79
2842779 | 지상 1층 | 지상 1층 | 2842071 | 1445 | 2.312 | 0.055488 | 1600
2842680 | 지상 1층 | 지상 1층 | 2842071 | 1445 | 2.312 | 0.055488 | 1600
2842899 | 지상 1층 | 지상 1층 | 2842071 | 1445 | 2.312 | 0.055488 | 1600
2843039 | 지상 1층 | 지상 1층 | 2842071 | 1445 | 2.312 | 0.055488 | 1600
2843113 | 지상 1층 | 지상 1층 | 2842071 | 1445 | 2.312 | 0.055488 | 1600
2843230 | 지상 1층 | 지상 1층 | 2842071 | 1445 | 2.5565 | 0.0613561 | 1769.21
2844151 | 지상 1층 | 지상 1층 | 2844131 | 2025 | 2.43 | 0.05832 | 1200
2844138 | 지상 1층 | 지상 1층 | 2844131 | 2025 | 2.43 | 0.05832 | 1200
2844159 | 지상 1층 | 지상 1층 | 2844131 | 2025 | 2.43 | 0.05832 | 1200
2844175 | 지상 1층 | 지상 1층 | 2844131 | 2025 | 2.49075 | 0.059778 | 1230
2844492 | 지상 1층 | 지상 1층 | 2844131 | 2025 | 2.49075 | 0.059778 | 1230
2844554 | 지상 1층 | 지상 1층 | 2844131 | 2025 | 2.78438 | 0.066825 | 1375
2844143 | 지상 1층 | 지상 1층 | 2844131 | 1345 | 1.37863 | 0.033087 | 1025
2844152 | 지상 1층 | 지상 1층 | 2844131 | 1345 | 1.614 | 0.038736 | 1200
2844144 | 지상 1층 | 지상 1층 | 2844131 | 1345 | 1.614 | 0.038736 | 1200
2844160 | 지상 1층 | 지상 1층 | 2844131 | 1345 | 1.614 | 0.038736 | 1200
2844168 | 지상 1층 | 지상 1층 | 2844131 | 1345 | 1.33155 | 0.0319572 | 990
2844176 | 지상 1층 | 지상 1층 | 2844131 | 1345 | 1.65435 | 0.0397044 | 1230
2844493 | 지상 1층 | 지상 1층 | 2844131 | 1345 | 1.65435 | 0.0397044 | 1230
2844555 | 지상 1층 | 지상 1층 | 2844131 | 1345 | 1.84938 | 0.044385 | 1375
2844808 | 지상 1층 | 지상 1층 | 2844807 | 1925 | 2.90166 | 0.0696397 | 1507.35
2845545 | 지상 1층 | 지상 1층 | 2844807 | 1925 | 2.695 | 0.06468 | 1400
2845607 | 지상 1층 | 지상 1층 | 2844807 | 1925 | 2.695 | 0.06468 | 1400
2845708 | 지상 1층 | 지상 1층 | 2844807 | 1925 | 2.695 | 0.06468 | 1400
2845802 | 지상 1층 | 지상 1층 | 2844807 | 1925 | 2.8875 | 0.0693 | 1500
2845916 | 지상 1층 | 지상 1층 | 2844807 | 1925 | 2.93494 | 0.0704387 | 1524.65
2845152 | 지상 1층 | 지상 1층 | 2844807 | 1445 | 2.17813 | 0.052275 | 1507.35
2845546 | 지상 1층 | 지상 1층 | 2844807 | 1445 | 2.023 | 0.048552 | 1400
2845608 | 지상 1층 | 지상 1층 | 2844807 | 1445 | 2.023 | 0.048552 | 1400
2845709 | 지상 1층 | 지상 1층 | 2844807 | 1445 | 2.023 | 0.048552 | 1400
2845803 | 지상 1층 | 지상 1층 | 2844807 | 1445 | 2.1675 | 0.05202 | 1500
2845917 | 지상 1층 | 지상 1층 | 2844807 | 1445 | 2.20311 | 0.0528747 | 1524.65
2847228 | 지상 1층 | 지상 1층 | 2847227 | 2025 | 2.44009 | 0.0585622 | 1204.98
2848230 | 지상 1층 | 지상 1층 | 2847227 | 2025 | 2.187 | 0.052488 | 1080
2848378 | 지상 1층 | 지상 1층 | 2847227 | 2025 | 3.0375 | 0.0729 | 1500
2848449 | 지상 1층 | 지상 1층 | 2847227 | 2025 | 3.0375 | 0.0729 | 1500
2848609 | 지상 1층 | 지상 1층 | 2847227 | 2025 | 2.268 | 0.054432 | 1120
2848785 | 지상 1층 | 지상 1층 | 2847227 | 2025 | 2.268 | 0.054432 | 1120
2849163 | 지상 1층 | 지상 1층 | 2847227 | 1345 | 1.6207 | 0.0388969 | 1204.98
2849164 | 지상 1층 | 지상 1층 | 2847227 | 1345 | 1.4526 | 0.0348624 | 1080
2849165 | 지상 1층 | 지상 1층 | 2847227 | 1345 | 1.27775 | 0.030666 | 950
2849166 | 지상 1층 | 지상 1층 | 2847227 | 1345 | 2.0175 | 0.04842 | 1500
2849167 | 지상 1층 | 지상 1층 | 2847227 | 1345 | 2.0175 | 0.04842 | 1500
2849168 | 지상 1층 | 지상 1층 | 2847227 | 1345 | 1.27775 | 0.030666 | 950
2849169 | 지상 1층 | 지상 1층 | 2847227 | 1345 | 1.5064 | 0.0361536 | 1120
2849171 | 지상 1층 | 지상 1층 | 2847227 | 1345 | 1.5064 | 0.0361536 | 1120
2849172 | 지상 1층 | 지상 1층 | 2847227 | 1345 | 1.31142 | 0.0314741 | 975.035
2850020 | 지상 1층 | 지상 1층 | 2850019 | 2025 | 0.6075 | 0.01458 | 300
2850730 | 지상 1층 | 지상 1층 | 2850019 | 2025 | 0.60743 | 0.0145783 | 299.965
2850883 | 지상 1층 | 지상 1층 | 2850019 | 2025 | 2.57175 | 0.061722 | 1270
2851632 | 지상 1층 | 지상 1층 | 2850019 | 2025 | 2.9262 | 0.0702287 | 1445.03
2851137 | 지상 1층 | 지상 1층 | 2850019 | 1845 | 2.20478 | 0.0529146 | 1195
2851139 | 지상 1층 | 지상 1층 | 2850019 | 1845 | 2.20471 | 0.0529131 | 1194.97
2851141 | 지상 1층 | 지상 1층 | 2850019 | 1845 | 1.98338 | 0.047601 | 1075
2851142 | 지상 1층 | 지상 1층 | 2850019 | 1845 | 2.34315 | 0.0562356 | 1270
2851633 | 지상 1층 | 지상 1층 | 2850019 | 1845 | 2.66609 | 0.0639861 | 1445.03
2852316 | 지상 1층 | 지상 1층 | 2851881 | 2025 | 3.02738 | 0.072657 | 1495
2852448 | 지상 1층 | 지상 1층 | 2851881 | 2025 | 3.02738 | 0.072657 | 1495
2852917 | 지상 1층 | 지상 1층 | 2851881 | 2025 | 2.69325 | 0.064638 | 1330
2853058 | 지상 1층 | 지상 1층 | 2851881 | 2025 | 2.80875 | 0.0674099 | 1387.03
2852131 | 지상 1층 | 지상 1층 | 2851881 | 1410 | 1.3747 | 0.0329928 | 974.965
2852317 | 지상 1층 | 지상 1층 | 2851881 | 1410 | 2.10795 | 0.0505908 | 1495
2852449 | 지상 1층 | 지상 1층 | 2851881 | 1410 | 2.10795 | 0.0505908 | 1495
2852564 | 지상 1층 | 지상 1층 | 2851881 | 1410 | 1.3395 | 0.032148 | 950
2852918 | 지상 1층 | 지상 1층 | 2851881 | 1410 | 1.8753 | 0.0450072 | 1330
2853059 | 지상 1층 | 지상 1층 | 2851881 | 1410 | 1.95572 | 0.0469373 | 1387.03
2852258 | 지상 1층 | 지상 1층 | 2851881 | 1385 | 1.35033 | 0.0324079 | 974.965
2852318 | 지상 1층 | 지상 1층 | 2851881 | 1385 | 2.07058 | 0.0496938 | 1495
2852450 | 지상 1층 | 지상 1층 | 2851881 | 1385 | 2.07058 | 0.0496938 | 1495
2852565 | 지상 1층 | 지상 1층 | 2851881 | 1385 | 1.31575 | 0.031578 | 950
2852919 | 지상 1층 | 지상 1층 | 2851881 | 1385 | 1.84205 | 0.0442092 | 1330
2853060 | 지상 1층 | 지상 1층 | 2851881 | 1385 | 1.92104 | 0.046105 | 1387.03
2854180 | 지상 1층 | 지상 1층 | 2853669 | 975 | 0.170625 | 0.004095 | 175
2854318 | 지상 1층 | 지상 1층 | 2853669 | 895 | 0.156625 | 0.003759 | 175
2855065 | 지상 1층 | 지상 1층 | 2855064 | 2025 | 2.2275 | 0.05346 | 1100
2855457 | 지상 1층 | 지상 1층 | 2855064 | 1345 | 1.4795 | 0.035508 | 1100
2855927 | 지상 1층 | 지상 1층 | 2855926 | 2025 | 8.63138 | 0.207153 | 4262.41
2856626 | 지상 1층 | 지상 1층 | 2855926 | 2025 | 1.27586 | 0.0306207 | 630.056
2857063 | 지상 1층 | 지상 1층 | 2855926 | 1345 | 8.73237 | 0.209577 | 6492.47
2857418 | 지상 1층 | 지상 1층 | 2857417 | 2025 | 0.556875 | 0.013365 | 275
2857424 | 지상 1층 | 지상 1층 | 2857417 | 2025 | 0.556875 | 0.013365 | 275
5476643 | 지상 1층 | 지상 1층 | 2857417 | 1845 | 4.428 | 0.106272 | 2400
2857503 | 지상 1층 | 지상 1층 | 2857502 | 2025 | 0.556672 | 0.0133601 | 274.9
2857509 | 지상 1층 | 지상 1층 | 2857502 | 2025 | 0.557113 | 0.0133707 | 275.118
2857519 | 지상 1층 | 지상 1층 | 2857502 | 1345 | 3.22802 | 0.0774726 | 2400.02
2864008 | 지상 1층 | 지상 1층 | 2864007 | 2025 | 2.835 | 0.06804 | 1400
5476611 | 지상 1층 | 지상 1층 | 2864007 | 2025 | 2.88562 | 0.069255 | 1425
5476609 | 지상 1층 | 지상 1층 | 2864007 | 2025 | 5.97375 | 0.14337 | 2950
5476612 | 지상 1층 | 지상 1층 | 2864007 | 2025 | 5.92313 | 0.142155 | 2925
2864721 | 지상 1층 | 지상 1층 | 2864007 | 1345 | 1.883 | 0.045192 | 1400
2864722 | 지상 1층 | 지상 1층 | 2864007 | 1345 | 1.91663 | 0.045999 | 1425
2864723 | 지상 1층 | 지상 1층 | 2864007 | 1345 | 3.96775 | 0.095226 | 2950
2864724 | 지상 1층 | 지상 1층 | 2864007 | 1345 | 3.93413 | 0.094419 | 2925
2865039 | 지상 1층 | 지상 1층 | 2865038 | 1505 | 3.36742 | 0.0808182 | 2237.49
5476620 | 지상 1층 | 지상 1층 | 2865038 | 1505 | 2.14462 | 0.051471 | 1425
5476619 | 지상 1층 | 지상 1층 | 2865038 | 1505 | 4.43975 | 0.106554 | 2950
5476621 | 지상 1층 | 지상 1층 | 2865038 | 1505 | 0.940625 | 0.022575 | 625
2865922 | 지상 1층 | 지상 1층 | 2865038 | 1725 | 3.85967 | 0.0926321 | 2237.49
2866260 | 지상 1층 | 지상 1층 | 2865038 | 1725 | 2.45812 | 0.058995 | 1425
2866127 | 지상 1층 | 지상 1층 | 2865038 | 1725 | 5.08875 | 0.12213 | 2950
2865966 | 지상 1층 | 지상 1층 | 2865038 | 1725 | 1.07813 | 0.025875 | 625
2867554 | 지상 1층 | 지상 1층 | 2867553 | 2025 | 2.27812 | 0.054675 | 1125
2868809 | 지상 1층 | 지상 1층 | 2867553 | 2025 | 4.75875 | 0.11421 | 2350
2868077 | 지상 1층 | 지상 1층 | 2867553 | 2025 | 5.4675 | 0.13122 | 2700
2868510 | 지상 1층 | 지상 1층 | 2867553 | 2025 | 4.60688 | 0.110565 | 2275
2868926 | 지상 1층 | 지상 1층 | 2867553 | 1345 | 1.51312 | 0.036315 | 1125
2868927 | 지상 1층 | 지상 1층 | 2867553 | 1345 | 3.16075 | 0.075858 | 2350
2868928 | 지상 1층 | 지상 1층 | 2867553 | 1345 | 3.6315 | 0.087156 | 2700
2868929 | 지상 1층 | 지상 1층 | 2867553 | 1345 | 1.27775 | 0.030666 | 950
2868930 | 지상 1층 | 지상 1층 | 2867553 | 1345 | 1.27775 | 0.030666 | 950
2868931 | 지상 1층 | 지상 1층 | 2867553 | 1345 | 3.05988 | 0.073437 | 2275
2870108 | 지상 1층 | 지상 1층 | 2870107 | 2025 | 4.10063 | 0.098415 | 2025
2871475 | 지상 1층 | 지상 1층 | 2870107 | 2025 | 4.96125 | 0.11907 | 2450
2871300 | 지상 1층 | 지상 1층 | 2870107 | 2025 | 4.96125 | 0.11907 | 2450
2871139 | 지상 1층 | 지상 1층 | 2870107 | 2025 | 4.75875 | 0.11421 | 2350
2871048 | 지상 1층 | 지상 1층 | 2870107 | 2025 | 2.27813 | 0.054675 | 1125
2871562 | 지상 1층 | 지상 1층 | 2870107 | 1345 | 2.72363 | 0.065367 | 2025
2871563 | 지상 1층 | 지상 1층 | 2870107 | 1345 | 3.29525 | 0.079086 | 2450
2871564 | 지상 1층 | 지상 1층 | 2870107 | 1345 | 3.29525 | 0.079086 | 2450
2871565 | 지상 1층 | 지상 1층 | 2870107 | 1345 | 3.16075 | 0.075858 | 2350
2871566 | 지상 1층 | 지상 1층 | 2870107 | 1345 | 1.51313 | 0.036315 | 1125
2873171 | 지상 1층 | 지상 1층 | 2872001 | 2025 | 3.79688 | 0.091125 | 1875
2873275 | 지상 1층 | 지상 1층 | 2872001 | 2025 | 3.99938 | 0.095985 | 1975
2873594 | 지상 1층 | 지상 1층 | 2872001 | 2025 | 3.77663 | 0.090639 | 1865
2873741 | 지상 1층 | 지상 1층 | 2872001 | 2025 | 3.969 | 0.095256 | 1960
2873070 | 지상 1층 | 지상 1층 | 2872001 | 1345 | 1.24413 | 0.029859 | 925
2873172 | 지상 1층 | 지상 1층 | 2872001 | 1345 | 2.52188 | 0.060525 | 1875
2873276 | 지상 1층 | 지상 1층 | 2872001 | 1345 | 2.65638 | 0.063753 | 1975
2873416 | 지상 1층 | 지상 1층 | 2872001 | 1345 | 1.27775 | 0.030666 | 950
2873595 | 지상 1층 | 지상 1층 | 2872001 | 1345 | 2.50843 | 0.0602022 | 1865
2873742 | 지상 1층 | 지상 1층 | 2872001 | 1345 | 2.6362 | 0.0632688 | 1960
2874842 | 지상 1층 | 지상 1층 | 2874145 | 2025 | 4.45493 | 0.106918 | 2199.97
2875034 | 지상 1층 | 지상 1층 | 2874145 | 2025 | 4.60691 | 0.110566 | 2275.02
2875119 | 지상 1층 | 지상 1층 | 2874145 | 1345 | 1.24413 | 0.029859 | 925
2875120 | 지상 1층 | 지상 1층 | 2874145 | 1345 | 2.95895 | 0.0710149 | 2199.97
2875121 | 지상 1층 | 지상 1층 | 2874145 | 1345 | 1.27775 | 0.030666 | 950
2875122 | 지상 1층 | 지상 1층 | 2874145 | 1345 | 3.0599 | 0.0734376 | 2275.02
2876415 | 지상 1층 | 지상 1층 | 2875696 | 2025 | 2.93625 | 0.07047 | 1450
2876574 | 지상 1층 | 지상 1층 | 2875696 | 2025 | 2.64256 | 0.0634213 | 1304.97
2876761 | 지상 1층 | 지상 1층 | 2875696 | 1345 | 1.24415 | 0.0298596 | 925.017
2876762 | 지상 1층 | 지상 1층 | 2875696 | 1345 | 1.95025 | 0.046806 | 1450
2876763 | 지상 1층 | 지상 1층 | 2875696 | 1345 | 1.75518 | 0.0421243 | 1304.97
2875828 | 지상 1층 | 지상 1층 | 2875827 | 2025 | 1.62234 | 0.0389361 | 801.153
2878324 | 지상 1층 | 지상 1층 | 2875827 | 2025 | 1.4013 | 0.0336312 | 692
2878088 | 지상 1층 | 지상 1층 | 2875827 | 1345 | 1.07755 | 0.0258612 | 801.153
2878156 | 지상 1층 | 지상 1층 | 2875827 | 1345 | 1.27775 | 0.030666 | 950
2878325 | 지상 1층 | 지상 1층 | 2875827 | 1345 | 0.93074 | 0.0223378 | 692
2880753 | 지상 2층 | 지상 2층 | 2880752 | 775 | 0.8525 | 0.02046 | 1100
2880759 | 지상 2층 | 지상 2층 | 2880752 | 1595 | 1.7545 | 0.042108 | 1100
2894517 | 지상 2층 | 지상 2층 | 2894516 | 575 | 0.519656 | 0.0124717 | 903.75
2894881 | 지상 2층 | 지상 2층 | 2894516 | 575 | 0.470781 | 0.0112988 | 818.75
2895002 | 지상 2층 | 지상 2층 | 2894516 | 575 | 0.470781 | 0.0112988 | 818.75
2895107 | 지상 2층 | 지상 2층 | 2894516 | 575 | 0.470781 | 0.0112988 | 818.75
2895233 | 지상 2층 | 지상 2층 | 2894516 | 575 | 0.470781 | 0.0112988 | 818.75
2895331 | 지상 2층 | 지상 2층 | 2894516 | 575 | 0.470781 | 0.0112988 | 818.75
2895421 | 지상 2층 | 지상 2층 | 2894516 | 575 | 0.470781 | 0.0112988 | 818.75
2895526 | 지상 2층 | 지상 2층 | 2894516 | 575 | 0.542656 | 0.0130238 | 943.75
2895953 | 지상 2층 | 지상 2층 | 2894516 | 300 | 0.271125 | 0.006507 | 903.75
2895954 | 지상 2층 | 지상 2층 | 2894516 | 300 | 0.245625 | 0.005895 | 818.75
2895955 | 지상 2층 | 지상 2층 | 2894516 | 300 | 0.245625 | 0.005895 | 818.75
2895956 | 지상 2층 | 지상 2층 | 2894516 | 300 | 0.245625 | 0.005895 | 818.75
2895957 | 지상 2층 | 지상 2층 | 2894516 | 300 | 0.245625 | 0.005895 | 818.75
2895958 | 지상 2층 | 지상 2층 | 2894516 | 300 | 0.245625 | 0.005895 | 818.75
2895959 | 지상 2층 | 지상 2층 | 2894516 | 300 | 0.245625 | 0.005895 | 818.75
2895960 | 지상 2층 | 지상 2층 | 2894516 | 300 | 0.283125 | 0.006795 | 943.75
2895807 | 지상 2층 | 지상 2층 | 2894516 | 1445 | 1.30592 | 0.031342 | 903.75
2895808 | 지상 2층 | 지상 2층 | 2894516 | 1445 | 1.18309 | 0.0283943 | 818.75
2895809 | 지상 2층 | 지상 2층 | 2894516 | 1445 | 1.18309 | 0.0283943 | 818.75
2895810 | 지상 2층 | 지상 2층 | 2894516 | 1445 | 1.18309 | 0.0283943 | 818.75
2895811 | 지상 2층 | 지상 2층 | 2894516 | 1445 | 1.18309 | 0.0283943 | 818.75
2895812 | 지상 2층 | 지상 2층 | 2894516 | 1445 | 1.18309 | 0.0283943 | 818.75
2895813 | 지상 2층 | 지상 2층 | 2894516 | 1445 | 1.18309 | 0.0283943 | 818.75
2895814 | 지상 2층 | 지상 2층 | 2894516 | 1445 | 1.36372 | 0.0327293 | 943.75
2897085 | 지상 2층 | 지상 2층 | 2897084 | 575 | 0.470771 | 0.0112985 | 818.733
2897490 | 지상 2층 | 지상 2층 | 2897084 | 575 | 0.427656 | 0.0102638 | 743.75
2897624 | 지상 2층 | 지상 2층 | 2897084 | 575 | 0.427656 | 0.0102638 | 743.75
2897713 | 지상 2층 | 지상 2층 | 2897084 | 575 | 0.427656 | 0.0102638 | 743.75
2897813 | 지상 2층 | 지상 2층 | 2897084 | 575 | 0.427656 | 0.0102638 | 743.75
2897902 | 지상 2층 | 지상 2층 | 2897084 | 575 | 0.427656 | 0.0102638 | 743.75
2897992 | 지상 2층 | 지상 2층 | 2897084 | 575 | 0.427656 | 0.0102638 | 743.75
2898086 | 지상 2층 | 지상 2층 | 2897084 | 575 | 0.499541 | 0.011989 | 868.767
2898340 | 지상 2층 | 지상 2층 | 2897084 | 300 | 0.24562 | 0.00589487 | 818.733
2898341 | 지상 2층 | 지상 2층 | 2897084 | 300 | 0.223125 | 0.005355 | 743.75
2898342 | 지상 2층 | 지상 2층 | 2897084 | 300 | 0.223125 | 0.005355 | 743.75
2898343 | 지상 2층 | 지상 2층 | 2897084 | 300 | 0.223125 | 0.005355 | 743.75
2898344 | 지상 2층 | 지상 2층 | 2897084 | 300 | 0.223125 | 0.005355 | 743.75
2898345 | 지상 2층 | 지상 2층 | 2897084 | 300 | 0.223125 | 0.005355 | 743.75
2898346 | 지상 2층 | 지상 2층 | 2897084 | 300 | 0.223125 | 0.005355 | 743.75
2898347 | 지상 2층 | 지상 2층 | 2897084 | 300 | 0.26063 | 0.00625513 | 868.767
2897561 | 지상 2층 | 지상 2층 | 2897084 | 1445 | 1.18307 | 0.0283936 | 818.733
2897562 | 지상 2층 | 지상 2층 | 2897084 | 1445 | 1.07472 | 0.0257933 | 743.75
2897625 | 지상 2층 | 지상 2층 | 2897084 | 1445 | 1.07472 | 0.0257933 | 743.75
2897714 | 지상 2층 | 지상 2층 | 2897084 | 1445 | 1.07472 | 0.0257933 | 743.75
2897814 | 지상 2층 | 지상 2층 | 2897084 | 1445 | 1.07472 | 0.0257933 | 743.75
2897903 | 지상 2층 | 지상 2층 | 2897084 | 1445 | 1.07472 | 0.0257933 | 743.75
2897993 | 지상 2층 | 지상 2층 | 2897084 | 1445 | 1.07472 | 0.0257933 | 743.75
2898087 | 지상 2층 | 지상 2층 | 2897084 | 1445 | 1.25537 | 0.0301289 | 868.767
2898537 | 지상 2층 | 지상 2층 | 2898536 | 575 | 0.463594 | 0.0111263 | 806.25
2898839 | 지상 2층 | 지상 2층 | 2898536 | 575 | 0.420469 | 0.0100913 | 731.25
2898881 | 지상 2층 | 지상 2층 | 2898536 | 575 | 0.420469 | 0.0100913 | 731.25
2898958 | 지상 2층 | 지상 2층 | 2898536 | 575 | 0.420469 | 0.0100913 | 731.25
2899039 | 지상 2층 | 지상 2층 | 2898536 | 575 | 0.420469 | 0.0100913 | 731.25
2899134 | 지상 2층 | 지상 2층 | 2898536 | 575 | 0.420469 | 0.0100913 | 731.25
2899229 | 지상 2층 | 지상 2층 | 2898536 | 575 | 0.420469 | 0.0100913 | 731.25
2899406 | 지상 2층 | 지상 2층 | 2898536 | 575 | 0.492344 | 0.0118162 | 856.25
2899733 | 지상 2층 | 지상 2층 | 2898536 | 300 | 0.241875 | 0.005805 | 806.25
2899734 | 지상 2층 | 지상 2층 | 2898536 | 300 | 0.219375 | 0.005265 | 731.25
2899735 | 지상 2층 | 지상 2층 | 2898536 | 300 | 0.219375 | 0.005265 | 731.25
2899736 | 지상 2층 | 지상 2층 | 2898536 | 300 | 0.219375 | 0.005265 | 731.25
2899737 | 지상 2층 | 지상 2층 | 2898536 | 300 | 0.219375 | 0.005265 | 731.25
2899738 | 지상 2층 | 지상 2층 | 2898536 | 300 | 0.219375 | 0.005265 | 731.25
2899739 | 지상 2층 | 지상 2층 | 2898536 | 300 | 0.219375 | 0.005265 | 731.25
2899740 | 지상 2층 | 지상 2층 | 2898536 | 300 | 0.256875 | 0.006165 | 856.25
2899549 | 지상 2층 | 지상 2층 | 2898536 | 1445 | 1.16503 | 0.0279608 | 806.25
2899550 | 지상 2층 | 지상 2층 | 2898536 | 1445 | 1.05666 | 0.0253598 | 731.25
2899551 | 지상 2층 | 지상 2층 | 2898536 | 1445 | 1.05666 | 0.0253598 | 731.25
2899552 | 지상 2층 | 지상 2층 | 2898536 | 1445 | 1.05666 | 0.0253598 | 731.25
2899553 | 지상 2층 | 지상 2층 | 2898536 | 1445 | 1.05666 | 0.0253598 | 731.25
2899554 | 지상 2층 | 지상 2층 | 2898536 | 1445 | 1.05666 | 0.0253598 | 731.25
2899555 | 지상 2층 | 지상 2층 | 2898536 | 1445 | 1.05666 | 0.0253598 | 731.25
2899556 | 지상 2층 | 지상 2층 | 2898536 | 1445 | 1.23728 | 0.0296947 | 856.25
2900184 | 지상 2층 | 지상 2층 | 2900183 | 575 | 0.437329 | 0.0104959 | 760.571
2900415 | 지상 2층 | 지상 2층 | 2900183 | 575 | 0.404554 | 0.00970929 | 703.571
2900488 | 지상 2층 | 지상 2층 | 2900183 | 575 | 0.404554 | 0.00970929 | 703.571
2900569 | 지상 2층 | 지상 2층 | 2900183 | 575 | 0.404554 | 0.00970929 | 703.571
2900658 | 지상 2층 | 지상 2층 | 2900183 | 575 | 0.404554 | 0.00970929 | 703.571
2900811 | 지상 2층 | 지상 2층 | 2900183 | 575 | 0.404554 | 0.00970929 | 703.571
2900891 | 지상 2층 | 지상 2층 | 2900183 | 575 | 0.390179 | 0.00936429 | 678.571
2901030 | 지상 2층 | 지상 2층 | 2900183 | 300 | 0.228171 | 0.00547611 | 760.571
2901031 | 지상 2층 | 지상 2층 | 2900183 | 300 | 0.211071 | 0.00506571 | 703.571
2901032 | 지상 2층 | 지상 2층 | 2900183 | 300 | 0.211071 | 0.00506571 | 703.571
2901033 | 지상 2층 | 지상 2층 | 2900183 | 300 | 0.211071 | 0.00506571 | 703.571
2901034 | 지상 2층 | 지상 2층 | 2900183 | 300 | 0.211071 | 0.00506571 | 703.571
2901035 | 지상 2층 | 지상 2층 | 2900183 | 300 | 0.211071 | 0.00506571 | 703.571
2901036 | 지상 2층 | 지상 2층 | 2900183 | 300 | 0.203571 | 0.00488571 | 678.571
2900730 | 지상 2층 | 지상 2층 | 2900183 | 1445 | 1.09903 | 0.0263766 | 760.571
2900731 | 지상 2층 | 지상 2층 | 2900183 | 1445 | 1.01666 | 0.0243999 | 703.571
2900732 | 지상 2층 | 지상 2층 | 2900183 | 1445 | 1.01666 | 0.0243999 | 703.571
2900733 | 지상 2층 | 지상 2층 | 2900183 | 1445 | 1.01666 | 0.0243999 | 703.571
2900734 | 지상 2층 | 지상 2층 | 2900183 | 1445 | 1.01666 | 0.0243999 | 703.571
2900812 | 지상 2층 | 지상 2층 | 2900183 | 1445 | 1.01666 | 0.0243999 | 703.571
2900892 | 지상 2층 | 지상 2층 | 2900183 | 1445 | 0.980536 | 0.0235329 | 678.571
2901337 | 지상 2층 | 지상 2층 | 2901336 | 575 | 0.376146 | 0.0090275 | 654.167
2901531 | 지상 2층 | 지상 2층 | 2901336 | 575 | 0.390521 | 0.0093725 | 679.167
2901568 | 지상 2층 | 지상 2층 | 2901336 | 575 | 0.390521 | 0.0093725 | 679.167
2901631 | 지상 2층 | 지상 2층 | 2901336 | 575 | 0.390521 | 0.0093725 | 679.167
2901694 | 지상 2층 | 지상 2층 | 2901336 | 575 | 0.390521 | 0.0093725 | 679.167
2901727 | 지상 2층 | 지상 2층 | 2901336 | 575 | 0.3461 | 0.0083064 | 601.913
2901955 | 지상 2층 | 지상 2층 | 2901336 | 300 | 0.19625 | 0.00471 | 654.167
2901956 | 지상 2층 | 지상 2층 | 2901336 | 300 | 0.20375 | 0.00489 | 679.167
2901957 | 지상 2층 | 지상 2층 | 2901336 | 300 | 0.20375 | 0.00489 | 679.167
2901958 | 지상 2층 | 지상 2층 | 2901336 | 300 | 0.20375 | 0.00489 | 679.167
2901959 | 지상 2층 | 지상 2층 | 2901336 | 300 | 0.20375 | 0.00489 | 679.167
2901960 | 지상 2층 | 지상 2층 | 2901336 | 300 | 0.180574 | 0.00433377 | 601.913
2901810 | 지상 2층 | 지상 2층 | 2901336 | 1445 | 0.945271 | 0.0226865 | 654.167
2901811 | 지상 2층 | 지상 2층 | 2901336 | 1445 | 0.981396 | 0.0235535 | 679.167
2901812 | 지상 2층 | 지상 2층 | 2901336 | 1445 | 0.981396 | 0.0235535 | 679.167
2901813 | 지상 2층 | 지상 2층 | 2901336 | 1445 | 0.981396 | 0.0235535 | 679.167
2901814 | 지상 2층 | 지상 2층 | 2901336 | 1445 | 0.981396 | 0.0235535 | 679.167
2901815 | 지상 2층 | 지상 2층 | 2901336 | 1445 | 0.869764 | 0.0208743 | 601.913
2902262 | 지상 2층 | 지상 2층 | 2902261 | 575 | 0.61929 | 0.014863 | 1077.03
2902540 | 지상 2층 | 지상 2층 | 2902261 | 575 | 0.5865 | 0.014076 | 1020
2902798 | 지상 2층 | 지상 2층 | 2902261 | 575 | 0.5865 | 0.014076 | 1020
2902853 | 지상 2층 | 지상 2층 | 2902261 | 575 | 0.5865 | 0.014076 | 1020
2902944 | 지상 2층 | 지상 2층 | 2902261 | 575 | 0.572125 | 0.013731 | 995
2903289 | 지상 2층 | 지상 2층 | 2902261 | 300 | 0.323108 | 0.00775459 | 1077.03
2903290 | 지상 2층 | 지상 2층 | 2902261 | 300 | 0.306 | 0.007344 | 1020
2903291 | 지상 2층 | 지상 2층 | 2902261 | 300 | 0.306 | 0.007344 | 1020
2903292 | 지상 2층 | 지상 2층 | 2902261 | 300 | 0.306 | 0.007344 | 1020
2903293 | 지상 2층 | 지상 2층 | 2902261 | 300 | 0.2985 | 0.007164 | 995
2903121 | 지상 2층 | 지상 2층 | 2902261 | 1445 | 1.5563 | 0.0373513 | 1077.03
2903122 | 지상 2층 | 지상 2층 | 2902261 | 1445 | 1.4739 | 0.0353736 | 1020
2903123 | 지상 2층 | 지상 2층 | 2902261 | 1445 | 1.4739 | 0.0353736 | 1020
2903124 | 지상 2층 | 지상 2층 | 2902261 | 1445 | 1.4739 | 0.0353736 | 1020
2903125 | 지상 2층 | 지상 2층 | 2902261 | 1445 | 1.43778 | 0.0345066 | 995
2903631 | 지상 2층 | 지상 2층 | 2903630 | 575 | 0.572125 | 0.013731 | 995
2903925 | 지상 2층 | 지상 2층 | 2903630 | 575 | 0.5865 | 0.014076 | 1020
2904008 | 지상 2층 | 지상 2층 | 2903630 | 575 | 0.5865 | 0.014076 | 1020
2904069 | 지상 2층 | 지상 2층 | 2903630 | 575 | 0.5865 | 0.014076 | 1020
2904223 | 지상 2층 | 지상 2층 | 2903630 | 575 | 0.629691 | 0.0151126 | 1095.11
2904636 | 지상 2층 | 지상 2층 | 2903630 | 300 | 0.2985 | 0.007164 | 995
2904637 | 지상 2층 | 지상 2층 | 2903630 | 300 | 0.306 | 0.007344 | 1020
2904638 | 지상 2층 | 지상 2층 | 2903630 | 300 | 0.306 | 0.007344 | 1020
2904639 | 지상 2층 | 지상 2층 | 2903630 | 300 | 0.306 | 0.007344 | 1020
2904640 | 지상 2층 | 지상 2층 | 2903630 | 300 | 0.328534 | 0.00788483 | 1095.11
2904433 | 지상 2층 | 지상 2층 | 2903630 | 1445 | 1.43778 | 0.0345066 | 995
2904434 | 지상 2층 | 지상 2층 | 2903630 | 1445 | 1.4739 | 0.0353736 | 1020
2904435 | 지상 2층 | 지상 2층 | 2903630 | 1445 | 1.4739 | 0.0353736 | 1020
2904436 | 지상 2층 | 지상 2층 | 2903630 | 1445 | 1.4739 | 0.0353736 | 1020
2904437 | 지상 2층 | 지상 2층 | 2903630 | 1445 | 1.58244 | 0.0379786 | 1095.11
2904975 | 지상 2층 | 지상 2층 | 2904974 | 575 | 0.675548 | 0.0162132 | 1174.87
2906907 | 지상 2층 | 지상 2층 | 2904974 | 575 | 0.675702 | 0.0162168 | 1175.13
2907152 | 지상 2층 | 지상 2층 | 2904974 | 300 | 0.35246 | 0.00845904 | 1174.87
2907153 | 지상 2층 | 지상 2층 | 2904974 | 300 | 0.35254 | 0.00846096 | 1175.13
2906996 | 지상 2층 | 지상 2층 | 2904974 | 1445 | 1.69768 | 0.0407444 | 1174.87
2906997 | 지상 2층 | 지상 2층 | 2904974 | 1445 | 1.69807 | 0.0407536 | 1175.13
2905065 | 지상 2층 | 지상 2층 | 2905064 | 575 | 0.633084 | 0.015194 | 1101.02
2907340 | 지상 2층 | 지상 2층 | 2905064 | 575 | 0.600156 | 0.0144038 | 1043.75
2907427 | 지상 2층 | 지상 2층 | 2905064 | 575 | 0.600156 | 0.0144038 | 1043.75
2907647 | 지상 2층 | 지상 2층 | 2905064 | 575 | 0.585781 | 0.0140588 | 1018.75
2907905 | 지상 2층 | 지상 2층 | 2905064 | 300 | 0.330305 | 0.00792732 | 1101.02
2907906 | 지상 2층 | 지상 2층 | 2905064 | 300 | 0.313125 | 0.007515 | 1043.75
2907907 | 지상 2층 | 지상 2층 | 2905064 | 300 | 0.313125 | 0.007515 | 1043.75
2907908 | 지상 2층 | 지상 2층 | 2905064 | 300 | 0.305625 | 0.007335 | 1018.75
2907506 | 지상 2층 | 지상 2층 | 2905064 | 1445 | 1.59097 | 0.0381832 | 1101.02
2907507 | 지상 2층 | 지상 2층 | 2905064 | 1445 | 1.50822 | 0.0361973 | 1043.75
2907508 | 지상 2층 | 지상 2층 | 2905064 | 1445 | 1.50822 | 0.0361973 | 1043.75
2907648 | 지상 2층 | 지상 2층 | 2905064 | 1445 | 1.47209 | 0.0353303 | 1018.75
2905218 | 지상 2층 | 지상 2층 | 2905217 | 575 | 0.585781 | 0.0140588 | 1018.75
2908431 | 지상 2층 | 지상 2층 | 2905217 | 575 | 0.600156 | 0.0144038 | 1043.75
2908688 | 지상 2층 | 지상 2층 | 2905217 | 575 | 0.600156 | 0.0144038 | 1043.75
2908760 | 지상 2층 | 지상 2층 | 2905217 | 575 | 0.628806 | 0.0150913 | 1093.57
2908571 | 지상 2층 | 지상 2층 | 2905217 | 300 | 0.305625 | 0.007335 | 1018.75
2908572 | 지상 2층 | 지상 2층 | 2905217 | 300 | 0.313125 | 0.007515 | 1043.75
2908689 | 지상 2층 | 지상 2층 | 2905217 | 300 | 0.313125 | 0.007515 | 1043.75
2908761 | 지상 2층 | 지상 2층 | 2905217 | 300 | 0.328072 | 0.00787374 | 1093.57
2908348 | 지상 2층 | 지상 2층 | 2905217 | 1445 | 1.47209 | 0.0353303 | 1018.75
2908432 | 지상 2층 | 지상 2층 | 2905217 | 1445 | 1.50822 | 0.0361973 | 1043.75
2908691 | 지상 2층 | 지상 2층 | 2905217 | 1445 | 1.50822 | 0.0361973 | 1043.75
2908763 | 지상 2층 | 지상 2층 | 2905217 | 1445 | 1.58022 | 0.0379252 | 1093.57
2905352 | 지상 2층 | 지상 2층 | 2905351 | 575 | 0.568444 | 0.0136427 | 988.599
2909310 | 지상 2층 | 지상 2층 | 2905351 | 575 | 0.539063 | 0.0129375 | 937.5
2909553 | 지상 2층 | 지상 2층 | 2905351 | 575 | 0.539063 | 0.0129375 | 937.5
2909653 | 지상 2층 | 지상 2층 | 2905351 | 575 | 0.524688 | 0.0125925 | 912.5
2909718 | 지상 2층 | 지상 2층 | 2905351 | 300 | 0.29658 | 0.00711791 | 988.599
2909719 | 지상 2층 | 지상 2층 | 2905351 | 300 | 0.28125 | 0.00675 | 937.5
2909720 | 지상 2층 | 지상 2층 | 2905351 | 300 | 0.28125 | 0.00675 | 937.5
2909721 | 지상 2층 | 지상 2층 | 2905351 | 300 | 0.27375 | 0.00657 | 912.5
2909229 | 지상 2층 | 지상 2층 | 2905351 | 1445 | 1.42853 | 0.0342846 | 988.599
2909311 | 지상 2층 | 지상 2층 | 2905351 | 1445 | 1.35469 | 0.0325125 | 937.5
2909555 | 지상 2층 | 지상 2층 | 2905351 | 1445 | 1.35469 | 0.0325125 | 937.5
2909655 | 지상 2층 | 지상 2층 | 2905351 | 1445 | 1.31856 | 0.0316455 | 912.5
2905463 | 지상 2층 | 지상 2층 | 2905462 | 575 | 0.524688 | 0.0125925 | 912.5
2910012 | 지상 2층 | 지상 2층 | 2905462 | 575 | 0.539063 | 0.0129375 | 937.5
2910171 | 지상 2층 | 지상 2층 | 2905462 | 575 | 0.539063 | 0.0129375 | 937.5
2910257 | 지상 2층 | 지상 2층 | 2905462 | 575 | 0.575954 | 0.0138229 | 1001.66
2910328 | 지상 2층 | 지상 2층 | 2905462 | 300 | 0.27375 | 0.00657 | 912.5
2910329 | 지상 2층 | 지상 2층 | 2905462 | 300 | 0.28125 | 0.00675 | 937.5
2910330 | 지상 2층 | 지상 2층 | 2905462 | 300 | 0.28125 | 0.00675 | 937.5
2910331 | 지상 2층 | 지상 2층 | 2905462 | 300 | 0.300498 | 0.00721194 | 1001.66
2909959 | 지상 2층 | 지상 2층 | 2905462 | 1445 | 1.31856 | 0.0316455 | 912.5
2910013 | 지상 2층 | 지상 2층 | 2905462 | 1445 | 1.35469 | 0.0325125 | 937.5
2910173 | 지상 2층 | 지상 2층 | 2905462 | 1445 | 1.35469 | 0.0325125 | 937.5
2910259 | 지상 2층 | 지상 2층 | 2905462 | 1445 | 1.4474 | 0.0347375 | 1001.66
2905549 | 지상 2층 | 지상 2층 | 2905548 | 575 | 0.466421 | 0.0111941 | 811.167
2911146 | 지상 2층 | 지상 2층 | 2905548 | 575 | 0.433646 | 0.0104075 | 754.167
2911233 | 지상 2층 | 지상 2층 | 2905548 | 575 | 0.433646 | 0.0104075 | 754.167
2911321 | 지상 2층 | 지상 2층 | 2905548 | 575 | 0.433646 | 0.0104075 | 754.167
2911397 | 지상 2층 | 지상 2층 | 2905548 | 575 | 0.433646 | 0.0104075 | 754.167
2911469 | 지상 2층 | 지상 2층 | 2905548 | 575 | 0.419271 | 0.0100625 | 729.167
2911662 | 지상 2층 | 지상 2층 | 2905548 | 300 | 0.24335 | 0.0058404 | 811.167
2911663 | 지상 2층 | 지상 2층 | 2905548 | 300 | 0.22625 | 0.00543 | 754.167
2911664 | 지상 2층 | 지상 2층 | 2905548 | 300 | 0.22625 | 0.00543 | 754.167
2911665 | 지상 2층 | 지상 2층 | 2905548 | 300 | 0.22625 | 0.00543 | 754.167
2911666 | 지상 2층 | 지상 2층 | 2905548 | 300 | 0.22625 | 0.00543 | 754.167
2911667 | 지상 2층 | 지상 2층 | 2905548 | 300 | 0.21875 | 0.00525 | 729.167
2911086 | 지상 2층 | 지상 2층 | 2905548 | 1445 | 1.17214 | 0.0281313 | 811.167
2911147 | 지상 2층 | 지상 2층 | 2905548 | 1445 | 1.08977 | 0.0261545 | 754.167
2911234 | 지상 2층 | 지상 2층 | 2905548 | 1445 | 1.08977 | 0.0261545 | 754.167
2911322 | 지상 2층 | 지상 2층 | 2905548 | 1445 | 1.08977 | 0.0261545 | 754.167
2911398 | 지상 2층 | 지상 2층 | 2905548 | 1445 | 1.08977 | 0.0261545 | 754.167
2911470 | 지상 2층 | 지상 2층 | 2905548 | 1445 | 1.05365 | 0.0252875 | 729.167
2905634 | 지상 2층 | 지상 2층 | 2905633 | 575 | 0.419271 | 0.0100625 | 729.167
2912121 | 지상 2층 | 지상 2층 | 2905633 | 575 | 0.433646 | 0.0104075 | 754.167
2912207 | 지상 2층 | 지상 2층 | 2905633 | 575 | 0.433646 | 0.0104075 | 754.167
2912261 | 지상 2층 | 지상 2층 | 2905633 | 575 | 0.433646 | 0.0104075 | 754.167
2912325 | 지상 2층 | 지상 2층 | 2905633 | 575 | 0.433646 | 0.0104075 | 754.167
2912395 | 지상 2층 | 지상 2층 | 2905633 | 575 | 0.466421 | 0.0111941 | 811.167
2912459 | 지상 2층 | 지상 2층 | 2905633 | 300 | 0.21875 | 0.00525 | 729.167
2912460 | 지상 2층 | 지상 2층 | 2905633 | 300 | 0.22625 | 0.00543 | 754.167
2912461 | 지상 2층 | 지상 2층 | 2905633 | 300 | 0.22625 | 0.00543 | 754.167
2912462 | 지상 2층 | 지상 2층 | 2905633 | 300 | 0.22625 | 0.00543 | 754.167
2912463 | 지상 2층 | 지상 2층 | 2905633 | 300 | 0.22625 | 0.00543 | 754.167
2912464 | 지상 2층 | 지상 2층 | 2905633 | 300 | 0.24335 | 0.0058404 | 811.167
2912022 | 지상 2층 | 지상 2층 | 2905633 | 1445 | 1.05365 | 0.0252875 | 729.167
2912122 | 지상 2층 | 지상 2층 | 2905633 | 1445 | 1.08977 | 0.0261545 | 754.167
2912208 | 지상 2층 | 지상 2층 | 2905633 | 1445 | 1.08977 | 0.0261545 | 754.167
2912262 | 지상 2층 | 지상 2층 | 2905633 | 1445 | 1.08977 | 0.0261545 | 754.167
2912326 | 지상 2층 | 지상 2층 | 2905633 | 1445 | 1.08977 | 0.0261545 | 754.167
2912396 | 지상 2층 | 지상 2층 | 2905633 | 1445 | 1.17214 | 0.0281313 | 811.167
2905748 | 지상 2층 | 지상 2층 | 2905747 | 575 | 0.481993 | 0.0115678 | 838.25
2912896 | 지상 2층 | 지상 2층 | 2905747 | 575 | 0.420469 | 0.0100913 | 731.25
2913065 | 지상 2층 | 지상 2층 | 2905747 | 575 | 0.420469 | 0.0100913 | 731.25
2913130 | 지상 2층 | 지상 2층 | 2905747 | 575 | 0.420469 | 0.0100913 | 731.25
2913199 | 지상 2층 | 지상 2층 | 2905747 | 575 | 0.420469 | 0.0100913 | 731.25
2913259 | 지상 2층 | 지상 2층 | 2905747 | 575 | 0.420469 | 0.0100913 | 731.25
2913387 | 지상 2층 | 지상 2층 | 2905747 | 575 | 0.420469 | 0.0100913 | 731.25
2913487 | 지상 2층 | 지상 2층 | 2905747 | 575 | 0.463594 | 0.0111263 | 806.25
2913560 | 지상 2층 | 지상 2층 | 2905747 | 300 | 0.251475 | 0.0060354 | 838.25
2913561 | 지상 2층 | 지상 2층 | 2905747 | 300 | 0.219375 | 0.005265 | 731.25
2913562 | 지상 2층 | 지상 2층 | 2905747 | 300 | 0.219375 | 0.005265 | 731.25
2913563 | 지상 2층 | 지상 2층 | 2905747 | 300 | 0.219375 | 0.005265 | 731.25
2913564 | 지상 2층 | 지상 2층 | 2905747 | 300 | 0.219375 | 0.005265 | 731.25
2913565 | 지상 2층 | 지상 2층 | 2905747 | 300 | 0.219375 | 0.005265 | 731.25
2913566 | 지상 2층 | 지상 2층 | 2905747 | 300 | 0.219375 | 0.005265 | 731.25
2913567 | 지상 2층 | 지상 2층 | 2905747 | 300 | 0.241875 | 0.005805 | 806.25
2912985 | 지상 2층 | 지상 2층 | 2905747 | 1445 | 1.21127 | 0.0290705 | 838.25
2912986 | 지상 2층 | 지상 2층 | 2905747 | 1445 | 1.05666 | 0.0253598 | 731.25
2913066 | 지상 2층 | 지상 2층 | 2905747 | 1445 | 1.05666 | 0.0253598 | 731.25
2913131 | 지상 2층 | 지상 2층 | 2905747 | 1445 | 1.05666 | 0.0253598 | 731.25
2913200 | 지상 2층 | 지상 2층 | 2905747 | 1445 | 1.05666 | 0.0253598 | 731.25
2913260 | 지상 2층 | 지상 2층 | 2905747 | 1445 | 1.05666 | 0.0253598 | 731.25
2913389 | 지상 2층 | 지상 2층 | 2905747 | 1445 | 1.05666 | 0.0253598 | 731.25
2913489 | 지상 2층 | 지상 2층 | 2905747 | 1445 | 1.16503 | 0.0279608 | 806.25
2905903 | 지상 2층 | 지상 2층 | 2905902 | 575 | 0.4945 | 0.011868 | 860
2913931 | 지상 2층 | 지상 2층 | 2905902 | 575 | 0.422625 | 0.010143 | 735
2914049 | 지상 2층 | 지상 2층 | 2905902 | 575 | 0.422625 | 0.010143 | 735
2914116 | 지상 2층 | 지상 2층 | 2905902 | 575 | 0.422625 | 0.010143 | 735
2914196 | 지상 2층 | 지상 2층 | 2905902 | 575 | 0.422625 | 0.010143 | 735
2914255 | 지상 2층 | 지상 2층 | 2905902 | 575 | 0.422625 | 0.010143 | 735
2914321 | 지상 2층 | 지상 2층 | 2905902 | 575 | 0.422625 | 0.010143 | 735
2914364 | 지상 2층 | 지상 2층 | 2905902 | 575 | 0.422625 | 0.010143 | 735
2914420 | 지상 2층 | 지상 2층 | 2905902 | 575 | 0.422625 | 0.010143 | 735
2914483 | 지상 2층 | 지상 2층 | 2905902 | 575 | 0.46575 | 0.011178 | 810
2914627 | 지상 2층 | 지상 2층 | 2905902 | 300 | 0.258 | 0.006192 | 860
2914628 | 지상 2층 | 지상 2층 | 2905902 | 300 | 0.2205 | 0.005292 | 735
2914629 | 지상 2층 | 지상 2층 | 2905902 | 300 | 0.2205 | 0.005292 | 735
2914630 | 지상 2층 | 지상 2층 | 2905902 | 300 | 0.2205 | 0.005292 | 735
2914631 | 지상 2층 | 지상 2층 | 2905902 | 300 | 0.2205 | 0.005292 | 735
2914632 | 지상 2층 | 지상 2층 | 2905902 | 300 | 0.2205 | 0.005292 | 735
2914633 | 지상 2층 | 지상 2층 | 2905902 | 300 | 0.2205 | 0.005292 | 735
2914634 | 지상 2층 | 지상 2층 | 2905902 | 300 | 0.2205 | 0.005292 | 735
2914635 | 지상 2층 | 지상 2층 | 2905902 | 300 | 0.2205 | 0.005292 | 735
2914636 | 지상 2층 | 지상 2층 | 2905902 | 300 | 0.243 | 0.005832 | 810
2913978 | 지상 2층 | 지상 2층 | 2905902 | 1445 | 1.2427 | 0.0298248 | 860
2913979 | 지상 2층 | 지상 2층 | 2905902 | 1445 | 1.06208 | 0.0254898 | 735
2914050 | 지상 2층 | 지상 2층 | 2905902 | 1445 | 1.06208 | 0.0254898 | 735
2914117 | 지상 2층 | 지상 2층 | 2905902 | 1445 | 1.06208 | 0.0254898 | 735
2914197 | 지상 2층 | 지상 2층 | 2905902 | 1445 | 1.06208 | 0.0254898 | 735
2914256 | 지상 2층 | 지상 2층 | 2905902 | 1445 | 1.06208 | 0.0254898 | 735
2914322 | 지상 2층 | 지상 2층 | 2905902 | 1445 | 1.06208 | 0.0254898 | 735
2914365 | 지상 2층 | 지상 2층 | 2905902 | 1445 | 1.06208 | 0.0254898 | 735
2914421 | 지상 2층 | 지상 2층 | 2905902 | 1445 | 1.06208 | 0.0254898 | 735
2914484 | 지상 2층 | 지상 2층 | 2905902 | 1445 | 1.17045 | 0.0280908 | 810
2914929 | 지상 2층 | 지상 2층 | 2914928 | 575 | 0.565986 | 0.0135837 | 984.323
2915239 | 지상 2층 | 지상 2층 | 2914928 | 575 | 0.539861 | 0.0129567 | 938.889
2915356 | 지상 2층 | 지상 2층 | 2914928 | 575 | 0.539861 | 0.0129567 | 938.889
2915440 | 지상 2층 | 지상 2층 | 2914928 | 575 | 0.539861 | 0.0129567 | 938.889
2915555 | 지상 2층 | 지상 2층 | 2914928 | 575 | 0.539861 | 0.0129567 | 938.889
2915661 | 지상 2층 | 지상 2층 | 2914928 | 575 | 0.539861 | 0.0129567 | 938.889
2915729 | 지상 2층 | 지상 2층 | 2914928 | 575 | 0.539861 | 0.0129567 | 938.889
2915795 | 지상 2층 | 지상 2층 | 2914928 | 575 | 0.539861 | 0.0129567 | 938.889
2915857 | 지상 2층 | 지상 2층 | 2914928 | 575 | 0.525486 | 0.0126117 | 913.889
2916006 | 지상 2층 | 지상 2층 | 2914928 | 300 | 0.295297 | 0.00708713 | 984.323
2916007 | 지상 2층 | 지상 2층 | 2914928 | 300 | 0.281667 | 0.00676 | 938.889
2916008 | 지상 2층 | 지상 2층 | 2914928 | 300 | 0.281667 | 0.00676 | 938.889
2916009 | 지상 2층 | 지상 2층 | 2914928 | 300 | 0.281667 | 0.00676 | 938.889
2916010 | 지상 2층 | 지상 2층 | 2914928 | 300 | 0.281667 | 0.00676 | 938.889
2916011 | 지상 2층 | 지상 2층 | 2914928 | 300 | 0.281667 | 0.00676 | 938.889
2916012 | 지상 2층 | 지상 2층 | 2914928 | 300 | 0.281667 | 0.00676 | 938.889
2916013 | 지상 2층 | 지상 2층 | 2914928 | 300 | 0.281667 | 0.00676 | 938.889
2916014 | 지상 2층 | 지상 2층 | 2914928 | 300 | 0.274167 | 0.00658 | 913.889
2915284 | 지상 2층 | 지상 2층 | 2914928 | 1445 | 1.42235 | 0.0341363 | 984.323
2915285 | 지상 2층 | 지상 2층 | 2914928 | 1445 | 1.35669 | 0.0325607 | 938.889
2915357 | 지상 2층 | 지상 2층 | 2914928 | 1445 | 1.35669 | 0.0325607 | 938.889
2915441 | 지상 2층 | 지상 2층 | 2914928 | 1445 | 1.35669 | 0.0325607 | 938.889
2915556 | 지상 2층 | 지상 2층 | 2914928 | 1445 | 1.35669 | 0.0325607 | 938.889
2915662 | 지상 2층 | 지상 2층 | 2914928 | 1445 | 1.35669 | 0.0325607 | 938.889
2915730 | 지상 2층 | 지상 2층 | 2914928 | 1445 | 1.35669 | 0.0325607 | 938.889
2915796 | 지상 2층 | 지상 2층 | 2914928 | 1445 | 1.35669 | 0.0325607 | 938.889
2915858 | 지상 2층 | 지상 2층 | 2914928 | 1445 | 1.32057 | 0.0316937 | 913.889
2917766 | 지상 3층 | 지상 3층 | 2917765 | 2025 | 1.06312 | 0.025515 | 525
2917785 | 지상 3층 | 지상 3층 | 2917765 | 2025 | 1.053 | 0.025272 | 520
2917772 | 지상 3층 | 지상 3층 | 2917765 | 445 | 0.233625 | 0.005607 | 525
2917778 | 지상 3층 | 지상 3층 | 2917765 | 445 | 0.669725 | 0.0160734 | 1505
2917786 | 지상 3층 | 지상 3층 | 2917765 | 445 | 0.2314 | 0.0055536 | 520
2918212 | 지상 2층 | 지상 2층 | 2918211 | 2025 | 4.58663 | 0.110079 | 2265
2918418 | 지상 2층 | 지상 2층 | 2918211 | 2025 | 5.33587 | 0.128061 | 2635
2918614 | 지상 2층 | 지상 2층 | 2918211 | 845 | 1.91393 | 0.0459342 | 2265
2918615 | 지상 2층 | 지상 2층 | 2918211 | 845 | 1.2675 | 0.03042 | 1500
2918616 | 지상 2층 | 지상 2층 | 2918211 | 845 | 2.22658 | 0.0534378 | 2635
2918868 | 지상 3층 | 지상 3층 | 2918867 | 2025 | 4.58663 | 0.110079 | 2265
2918874 | 지상 3층 | 지상 3층 | 2918867 | 2025 | 5.33587 | 0.128061 | 2635
2918884 | 지상 3층 | 지상 3층 | 2918867 | 445 | 1.00793 | 0.0241902 | 2265
2918885 | 지상 3층 | 지상 3층 | 2918867 | 445 | 0.6675 | 0.01602 | 1500
2918886 | 지상 3층 | 지상 3층 | 2918867 | 445 | 1.17258 | 0.0281418 | 2635
2919134 | 지상 10층 | 지상 10층 | 2919133 | 2075 | 4.80355 | 0.115285 | 2314.97
2919140 | 지상 10층 | 지상 10층 | 2919133 | 2075 | 5.57145 | 0.133715 | 2685.03
2919150 | 지상 10층 | 지상 10층 | 2919133 | 1345 | 3.11363 | 0.0747271 | 2314.97
2919151 | 지상 10층 | 지상 10층 | 2919133 | 1345 | 2.0175 | 0.04842 | 1500
2919152 | 지상 10층 | 지상 10층 | 2919133 | 1345 | 3.61137 | 0.0866729 | 2685.03
2919262 | 지상 2층 | 지상 2층 | 2919261 | 2025 | 4.5867 | 0.110081 | 2265.03
2919555 | 지상 2층 | 지상 2층 | 2919261 | 2025 | 5.1333 | 0.123199 | 2534.97
2919677 | 지상 2층 | 지상 2층 | 2919261 | 845 | 1.91395 | 0.0459349 | 2265.03
2919678 | 지상 2층 | 지상 2층 | 2919261 | 845 | 1.2675 | 0.03042 | 1500
2919679 | 지상 2층 | 지상 2층 | 2919261 | 845 | 2.14205 | 0.0514091 | 2534.97
2919870 | 지상 9층 | 지상 9층 | 2919869 | 2075 | 4.90738 | 0.117777 | 2365
2919876 | 지상 9층 | 지상 9층 | 2919869 | 2075 | 5.6752 | 0.136205 | 2735.03
2919886 | 지상 9층 | 지상 9층 | 2919869 | 845 | 1.99843 | 0.0479622 | 2365
2919887 | 지상 9층 | 지상 9층 | 2919869 | 845 | 1.2675 | 0.03042 | 1500
2919888 | 지상 9층 | 지상 9층 | 2919869 | 845 | 2.3111 | 0.0554665 | 2735.03
2920060 | 지상 9층 | 지상 9층 | 2920059 | 2075 | 4.69995 | 0.112799 | 2265.03
2920066 | 지상 9층 | 지상 9층 | 2920059 | 2075 | 5.26013 | 0.126243 | 2535
2920076 | 지상 9층 | 지상 9층 | 2920059 | 845 | 1.91395 | 0.0459349 | 2265.03
2920077 | 지상 9층 | 지상 9층 | 2920059 | 845 | 1.2675 | 0.03042 | 1500
2920078 | 지상 9층 | 지상 9층 | 2920059 | 845 | 2.14208 | 0.0514098 | 2535
2920394 | 지상 4층 | 지상 4층 | 2920393 | 2075 | 4.69995 | 0.112799 | 2265.03
2920400 | 지상 4층 | 지상 4층 | 2920393 | 2075 | 5.26005 | 0.126241 | 2534.97
2920410 | 지상 4층 | 지상 4층 | 2920393 | 445 | 1.00794 | 0.0241906 | 2265.03
2920411 | 지상 4층 | 지상 4층 | 2920393 | 445 | 0.6675 | 0.01602 | 1500
2920412 | 지상 4층 | 지상 4층 | 2920393 | 445 | 1.12806 | 0.0270734 | 2534.97
2920539 | 지상 10층 | 지상 10층 | 2920538 | 2075 | 4.69995 | 0.112799 | 2265.03
2920545 | 지상 10층 | 지상 10층 | 2920538 | 2075 | 5.25857 | 0.126206 | 2534.25
2920555 | 지상 10층 | 지상 10층 | 2920538 | 1345 | 3.04647 | 0.0731153 | 2265.03
2920556 | 지상 10층 | 지상 10층 | 2920538 | 1345 | 2.0175 | 0.04842 | 1500
2920557 | 지상 10층 | 지상 10층 | 2920538 | 1345 | 3.40857 | 0.0818056 | 2534.25
2920612 | 지상 2층 | 지상 2층 | 2920611 | 2025 | 0.763079 | 0.0183139 | 376.829
2920631 | 지상 2층 | 지상 2층 | 2920611 | 2025 | 0.85687 | 0.0205649 | 423.145
2920618 | 지상 2층 | 지상 2층 | 2920611 | 845 | 0.318421 | 0.0076421 | 376.829
2920624 | 지상 2층 | 지상 2층 | 2920611 | 845 | 1.2675 | 0.03042 | 1500
2920632 | 지상 2층 | 지상 2층 | 2920611 | 845 | 0.357558 | 0.00858139 | 423.145
2920735 | 지상 2층 | 지상 2층 | 2920734 | 2025 | 3.61463 | 0.086751 | 1785
2921189 | 지상 2층 | 지상 2층 | 2920734 | 2025 | 3.66525 | 0.087966 | 1810
2921328 | 지상 2층 | 지상 2층 | 2920734 | 2025 | 4.9005 | 0.117612 | 2420
2921434 | 지상 2층 | 지상 2층 | 2920734 | 2025 | 4.22212 | 0.101331 | 2085
2921140 | 지상 2층 | 지상 2층 | 2920734 | 845 | 1.50833 | 0.0361998 | 1785
2921190 | 지상 2층 | 지상 2층 | 2920734 | 845 | 1.52945 | 0.0367068 | 1810
2921271 | 지상 2층 | 지상 2층 | 2920734 | 845 | 1.2675 | 0.03042 | 1500
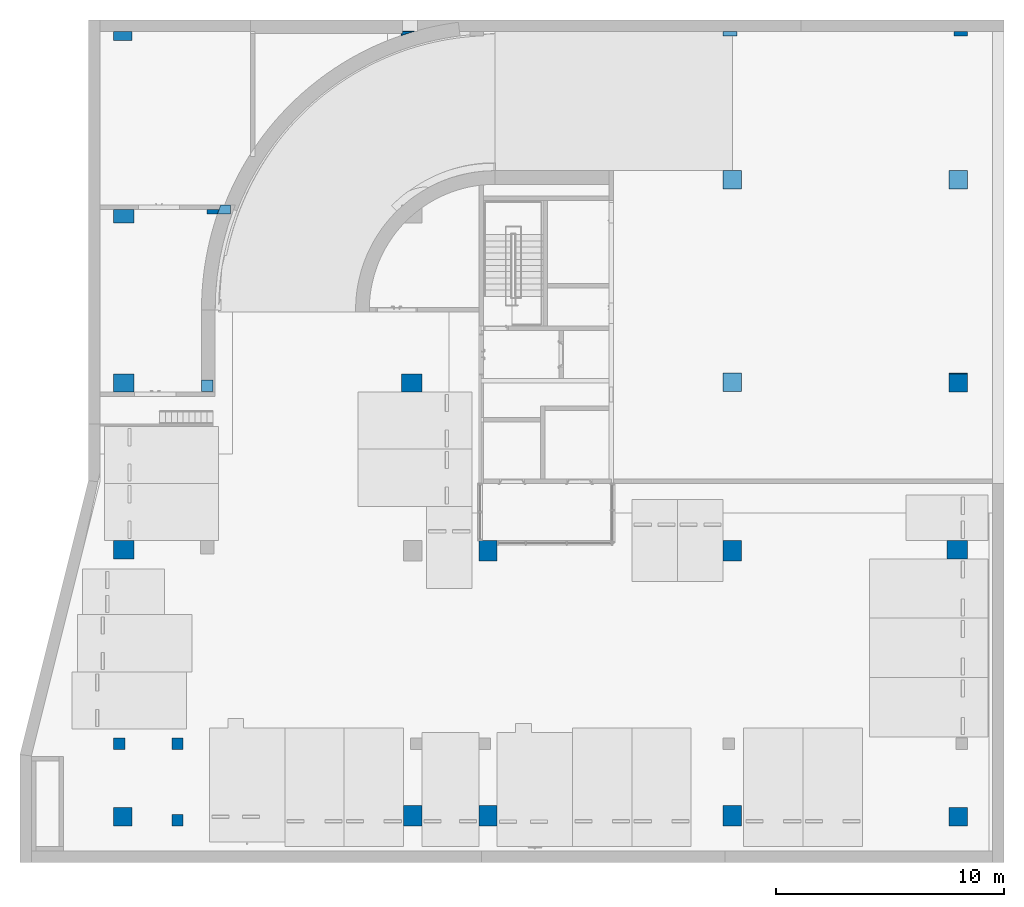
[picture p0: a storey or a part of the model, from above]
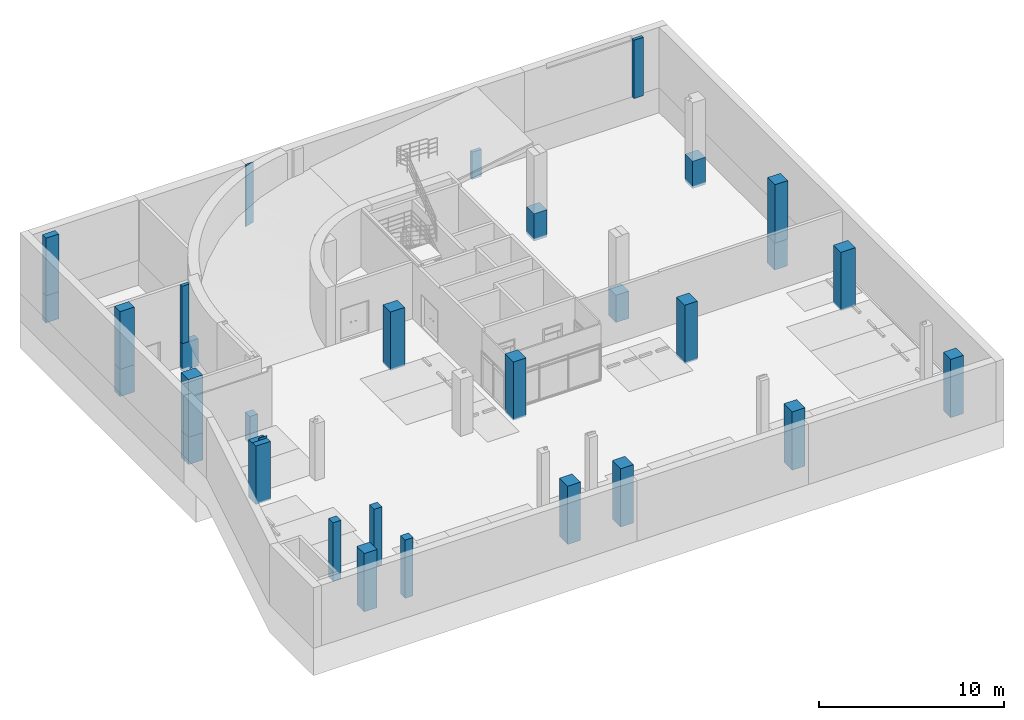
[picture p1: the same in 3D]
Properties of the parts of a building model (IFC2X3), part 29 of 39

# IfcPlate: CW300-THK24.Low-e coating glass:CW300-THK24.Low-e coating glass (2337)
Name (CW300-THK24.Low-e coating glass:CW300-THK24.Low-e coating glass:...) | In | 레벨 | 호스트 ID | 높이 (mm) | 면적 (m2) | 체적 (m3) = NetVolume (m3) | 폭 (mm)
2921329 | 지상 2층 | 지상 2층 | 2920734 | 845 | 2.0449 | 0.0490776 | 2420
2921435 | 지상 2층 | 지상 2층 | 2920734 | 845 | 1.76183 | 0.0422838 | 2085
2921996 | 지상 3층 | 지상 3층 | 2921989 | 445 | 0.167697 | 0.00402472 | 376.847
2922002 | 지상 3층 | 지상 3층 | 2921989 | 445 | 0.6675 | 0.01602 | 1500
2922010 | 지상 3층 | 지상 3층 | 2921989 | 445 | 0.1883 | 0.00451919 | 423.145
2922170 | 지상 9층 | 지상 9층 | 2922163 | 845 | 0.316875 | 0.007605 | 375
2922176 | 지상 9층 | 지상 9층 | 2922163 | 845 | 1.2675 | 0.03042 | 1500
2922184 | 지상 9층 | 지상 9층 | 2922163 | 845 | 0.359125 | 0.008619 | 425
2922199 | 지상 10층 | 지상 10층 | 2922192 | 1345 | 0.504375 | 0.012105 | 375
2922205 | 지상 10층 | 지상 10층 | 2922192 | 1345 | 2.0175 | 0.04842 | 1500
2922213 | 지상 10층 | 지상 10층 | 2922192 | 1345 | 0.571625 | 0.013719 | 425
2923036 | 지상 3층 | 지상 3층 | 2923035 | 2075 | 3.70391 | 0.0888939 | 1785.02
2923047 | 지상 3층 | 지상 3층 | 2923035 | 2075 | 3.75575 | 0.090138 | 1810
2923063 | 지상 3층 | 지상 3층 | 2923035 | 2075 | 4.37825 | 0.105078 | 2110
2923071 | 지상 3층 | 지상 3층 | 2923035 | 2075 | 4.32637 | 0.103833 | 2085
2923042 | 지상 3층 | 지상 3층 | 2923035 | 445 | 0.794333 | 0.019064 | 1785.02
2923048 | 지상 3층 | 지상 3층 | 2923035 | 445 | 0.80545 | 0.0193308 | 1810
2923056 | 지상 3층 | 지상 3층 | 2923035 | 445 | 0.80545 | 0.0193308 | 1810
2923064 | 지상 3층 | 지상 3층 | 2923035 | 445 | 0.93895 | 0.0225348 | 2110
2923072 | 지상 3층 | 지상 3층 | 2923035 | 445 | 0.927825 | 0.0222678 | 2085
2923306 | 지상 9층 | 지상 9층 | 2923305 | 2075 | 3.91138 | 0.093873 | 1885
2923317 | 지상 9층 | 지상 9층 | 2923305 | 2075 | 3.75575 | 0.090138 | 1810
2923333 | 지상 9층 | 지상 9층 | 2923305 | 2075 | 5.0215 | 0.120516 | 2420
2923341 | 지상 9층 | 지상 9층 | 2923305 | 2075 | 4.32637 | 0.103833 | 2085
2923312 | 지상 9층 | 지상 9층 | 2923305 | 845 | 1.59283 | 0.0382278 | 1885
2923318 | 지상 9층 | 지상 9층 | 2923305 | 845 | 1.52945 | 0.0367068 | 1810
2923326 | 지상 9층 | 지상 9층 | 2923305 | 845 | 1.2675 | 0.03042 | 1500
2923334 | 지상 9층 | 지상 9층 | 2923305 | 845 | 2.0449 | 0.0490776 | 2420
2923342 | 지상 9층 | 지상 9층 | 2923305 | 845 | 1.76183 | 0.0422838 | 2085
2923351 | 지상 10층 | 지상 10층 | 2923350 | 2075 | 3.91138 | 0.093873 | 1885
2923362 | 지상 10층 | 지상 10층 | 2923350 | 2075 | 3.75575 | 0.090138 | 1810
2923378 | 지상 10층 | 지상 10층 | 2923350 | 2075 | 5.0215 | 0.120516 | 2420
2923386 | 지상 10층 | 지상 10층 | 2923350 | 2075 | 4.32637 | 0.103833 | 2085
2923357 | 지상 10층 | 지상 10층 | 2923350 | 1345 | 2.53533 | 0.0608478 | 1885
2923363 | 지상 10층 | 지상 10층 | 2923350 | 1345 | 2.43445 | 0.0584268 | 1810
2923371 | 지상 10층 | 지상 10층 | 2923350 | 1345 | 2.0175 | 0.04842 | 1500
2923379 | 지상 10층 | 지상 10층 | 2923350 | 1345 | 3.2549 | 0.0781176 | 2420
2923387 | 지상 10층 | 지상 10층 | 2923350 | 1345 | 2.80433 | 0.0673038 | 2085
2923463 | 지상 2층 | 지상 2층 | 2923462 | 2025 | 4.1877 | 0.100505 | 2068
2924239 | 지상 2층 | 지상 2층 | 2923462 | 845 | 1.74746 | 0.041939 | 2068
2923550 | 지상 2층 | 지상 2층 | 2923549 | 2025 | 0.93754 | 0.022501 | 462.983
2924623 | 지상 2층 | 지상 2층 | 2923549 | 2025 | 0.92745 | 0.0222588 | 458
2924458 | 지상 2층 | 지상 2층 | 2923549 | 845 | 0.39122 | 0.00938929 | 462.983
2924459 | 지상 2층 | 지상 2층 | 2923549 | 845 | 1.2675 | 0.03042 | 1500
2924624 | 지상 2층 | 지상 2층 | 2923549 | 845 | 0.38701 | 0.00928824 | 458
2923616 | 지상 2층 | 지상 2층 | 2923615 | 2025 | 1.58557 | 0.0380538 | 783
7694595 | 지상 2층 | 지상 2층 | 2923615 | 2075 | 0.581018 | 0.0139444 | 280.009
2924895 | 지상 2층 | 지상 2층 | 2923615 | 845 | 0.661635 | 0.0158792 | 783
2925047 | 지상 2층 | 지상 2층 | 2923615 | 845 | 1.26328 | 0.0303186 | 1495
7694596 | 지상 2층 | 지상 2층 | 2923615 | 845 | 0.236607 | 0.00567858 | 280.009
2926332 | 지상 3층 | 지상 3층 | 2926331 | 825 | 0.721614 | 0.0173187 | 874.684
2926466 | 지상 3층 | 지상 3층 | 2926331 | 825 | 0.927864 | 0.0222687 | 1124.68
2926467 | 지상 3층 | 지상 3층 | 2926331 | 450 | 0.506108 | 0.0121466 | 1124.68
2926338 | 지상 3층 | 지상 3층 | 2926331 | 1145 | 1.00151 | 0.0240363 | 874.684
2926468 | 지상 3층 | 지상 3층 | 2926331 | 1145 | 1.28776 | 0.0309063 | 1124.68
2927265 | 지상 3층 | 지상 3층 | 2927264 | 875 | 0.681324 | 0.0163518 | 778.655
2929639 | 지상 3층 | 지상 3층 | 2927264 | 875 | 0.78225 | 0.018774 | 894
2929783 | 지상 3층 | 지상 3층 | 2927264 | 875 | 0.7035 | 0.016884 | 804
2930133 | 지상 3층 | 지상 3층 | 2927264 | 875 | 0.7035 | 0.016884 | 804
2930221 | 지상 3층 | 지상 3층 | 2927264 | 875 | 0.7035 | 0.016884 | 804
2930309 | 지상 3층 | 지상 3층 | 2927264 | 875 | 0.7035 | 0.016884 | 804
2930391 | 지상 3층 | 지상 3층 | 2927264 | 875 | 0.7035 | 0.016884 | 804
2930473 | 지상 3층 | 지상 3층 | 2927264 | 875 | 0.7035 | 0.016884 | 804
2930517 | 지상 3층 | 지상 3층 | 2927264 | 875 | 0.756 | 0.018144 | 864
2930555 | 지상 3층 | 지상 3층 | 2927264 | 875 | 0.875 | 0.021 | 1000
2930631 | 지상 3층 | 지상 3층 | 2927264 | 875 | 0.690375 | 0.016569 | 789
2930669 | 지상 3층 | 지상 3층 | 2927264 | 875 | 0.637875 | 0.015309 | 729
2930707 | 지상 3층 | 지상 3층 | 2927264 | 875 | 0.637875 | 0.015309 | 729
2930789 | 지상 3층 | 지상 3층 | 2927264 | 875 | 0.637875 | 0.015309 | 729
2930827 | 지상 3층 | 지상 3층 | 2927264 | 875 | 0.637875 | 0.015309 | 729
2930865 | 지상 3층 | 지상 3층 | 2927264 | 875 | 0.637875 | 0.015309 | 729
2930903 | 지상 3층 | 지상 3층 | 2927264 | 875 | 0.637875 | 0.015309 | 729
2930941 | 지상 3층 | 지상 3층 | 2927264 | 875 | 0.690375 | 0.016569 | 789
2930985 | 지상 3층 | 지상 3층 | 2927264 | 875 | 0.875 | 0.021 | 1000
2931107 | 지상 3층 | 지상 3층 | 2927264 | 875 | 0.679 | 0.016296 | 776
2931064 | 지상 3층 | 지상 3층 | 2927264 | 875 | 0.6265 | 0.015036 | 716
2931142 | 지상 3층 | 지상 3층 | 2927264 | 875 | 0.6265 | 0.015036 | 716
2934161 | 지상 3층 | 지상 3층 | 2927264 | 875 | 0.6265 | 0.015036 | 716
2934126 | 지상 3층 | 지상 3층 | 2927264 | 875 | 0.6265 | 0.015036 | 716
2931180 | 지상 3층 | 지상 3층 | 2927264 | 875 | 0.6265 | 0.015036 | 716
2931256 | 지상 3층 | 지상 3층 | 2927264 | 875 | 0.6265 | 0.015036 | 716
2931297 | 지상 3층 | 지상 3층 | 2927264 | 875 | 0.679 | 0.016296 | 776
2935113 | 지상 3층 | 지상 3층 | 2927264 | 875 | 0.86625 | 0.02079 | 990
2931376 | 지상 3층 | 지상 3층 | 2927264 | 875 | 0.68775 | 0.016506 | 786
2931414 | 지상 3층 | 지상 3층 | 2927264 | 875 | 0.6265 | 0.015036 | 716
2933432 | 지상 3층 | 지상 3층 | 2927264 | 875 | 0.6265 | 0.015036 | 716
2933399 | 지상 3층 | 지상 3층 | 2927264 | 875 | 0.6265 | 0.015036 | 716
2933364 | 지상 3층 | 지상 3층 | 2927264 | 875 | 0.6265 | 0.015036 | 716
2933329 | 지상 3층 | 지상 3층 | 2927264 | 875 | 0.6265 | 0.015036 | 716
2933294 | 지상 3층 | 지상 3층 | 2927264 | 875 | 0.6265 | 0.015036 | 716
2933261 | 지상 3층 | 지상 3층 | 2927264 | 875 | 0.6265 | 0.015036 | 716
2933226 | 지상 3층 | 지상 3층 | 2927264 | 875 | 0.6265 | 0.015036 | 716
2933191 | 지상 3층 | 지상 3층 | 2927264 | 875 | 0.6265 | 0.015036 | 716
2933158 | 지상 3층 | 지상 3층 | 2927264 | 875 | 0.6265 | 0.015036 | 716
2931490 | 지상 3층 | 지상 3층 | 2927264 | 875 | 0.6265 | 0.015036 | 716
2931528 | 지상 3층 | 지상 3층 | 2927264 | 875 | 0.56175 | 0.013482 | 642
2931566 | 지상 3층 | 지상 3층 | 2927264 | 875 | 0.641375 | 0.015393 | 733
2931604 | 지상 3층 | 지상 3층 | 2927264 | 875 | 0.798301 | 0.0191592 | 912.345
2929435 | 지상 3층 | 지상 3층 | 2927264 | 550 | 0.428261 | 0.0102783 | 778.655
2930556 | 지상 3층 | 지상 3층 | 2927264 | 550 | 0.55 | 0.0132 | 1000
2930986 | 지상 3층 | 지상 3층 | 2927264 | 550 | 0.55 | 0.0132 | 1000
2935114 | 지상 3층 | 지상 3층 | 2927264 | 550 | 0.5445 | 0.013068 | 990
2931605 | 지상 3층 | 지상 3층 | 2927264 | 550 | 0.501789 | 0.0120429 | 912.345
2929180 | 지상 3층 | 지상 3층 | 2927264 | 995 | 0.774762 | 0.0185943 | 778.655
2929641 | 지상 3층 | 지상 3층 | 2927264 | 995 | 0.88953 | 0.0213487 | 894
2929785 | 지상 3층 | 지상 3층 | 2927264 | 995 | 0.79998 | 0.0191995 | 804
2930135 | 지상 3층 | 지상 3층 | 2927264 | 995 | 0.79998 | 0.0191995 | 804
2930223 | 지상 3층 | 지상 3층 | 2927264 | 995 | 0.79998 | 0.0191995 | 804
2930311 | 지상 3층 | 지상 3층 | 2927264 | 995 | 0.79998 | 0.0191995 | 804
2930393 | 지상 3층 | 지상 3층 | 2927264 | 995 | 0.79998 | 0.0191995 | 804
2930475 | 지상 3층 | 지상 3층 | 2927264 | 995 | 0.79998 | 0.0191995 | 804
2930519 | 지상 3층 | 지상 3층 | 2927264 | 995 | 0.85968 | 0.0206323 | 864
2930557 | 지상 3층 | 지상 3층 | 2927264 | 995 | 0.995 | 0.02388 | 1000
2930633 | 지상 3층 | 지상 3층 | 2927264 | 995 | 0.785055 | 0.0188413 | 789
2930671 | 지상 3층 | 지상 3층 | 2927264 | 995 | 0.725355 | 0.0174085 | 729
2930709 | 지상 3층 | 지상 3층 | 2927264 | 995 | 0.725355 | 0.0174085 | 729
2930791 | 지상 3층 | 지상 3층 | 2927264 | 995 | 0.725355 | 0.0174085 | 729
2930829 | 지상 3층 | 지상 3층 | 2927264 | 995 | 0.725355 | 0.0174085 | 729
2930867 | 지상 3층 | 지상 3층 | 2927264 | 995 | 0.725355 | 0.0174085 | 729
2930905 | 지상 3층 | 지상 3층 | 2927264 | 995 | 0.725355 | 0.0174085 | 729
2930943 | 지상 3층 | 지상 3층 | 2927264 | 995 | 0.785055 | 0.0188413 | 789
2930987 | 지상 3층 | 지상 3층 | 2927264 | 995 | 0.995 | 0.02388 | 1000
2931109 | 지상 3층 | 지상 3층 | 2927264 | 995 | 0.77212 | 0.0185309 | 776
2931066 | 지상 3층 | 지상 3층 | 2927264 | 995 | 0.71242 | 0.0170981 | 716
2931144 | 지상 3층 | 지상 3층 | 2927264 | 995 | 0.71242 | 0.0170981 | 716
2934163 | 지상 3층 | 지상 3층 | 2927264 | 995 | 0.71242 | 0.0170981 | 716
2934128 | 지상 3층 | 지상 3층 | 2927264 | 995 | 0.71242 | 0.0170981 | 716
2931182 | 지상 3층 | 지상 3층 | 2927264 | 995 | 0.71242 | 0.0170981 | 716
2931258 | 지상 3층 | 지상 3층 | 2927264 | 995 | 0.71242 | 0.0170981 | 716
2931299 | 지상 3층 | 지상 3층 | 2927264 | 995 | 0.77212 | 0.0185309 | 776
2935115 | 지상 3층 | 지상 3층 | 2927264 | 995 | 0.98505 | 0.0236412 | 990
2931378 | 지상 3층 | 지상 3층 | 2927264 | 995 | 0.78207 | 0.0187697 | 786
2931416 | 지상 3층 | 지상 3층 | 2927264 | 995 | 0.71242 | 0.0170981 | 716
2933434 | 지상 3층 | 지상 3층 | 2927264 | 995 | 0.71242 | 0.0170981 | 716
2933401 | 지상 3층 | 지상 3층 | 2927264 | 995 | 0.71242 | 0.0170981 | 716
2933366 | 지상 3층 | 지상 3층 | 2927264 | 995 | 0.71242 | 0.0170981 | 716
2933331 | 지상 3층 | 지상 3층 | 2927264 | 995 | 0.71242 | 0.0170981 | 716
2933296 | 지상 3층 | 지상 3층 | 2927264 | 995 | 0.71242 | 0.0170981 | 716
2933263 | 지상 3층 | 지상 3층 | 2927264 | 995 | 0.71242 | 0.0170981 | 716
2933228 | 지상 3층 | 지상 3층 | 2927264 | 995 | 0.71242 | 0.0170981 | 716
2933193 | 지상 3층 | 지상 3층 | 2927264 | 995 | 0.71242 | 0.0170981 | 716
2933160 | 지상 3층 | 지상 3층 | 2927264 | 995 | 0.71242 | 0.0170981 | 716
2931492 | 지상 3층 | 지상 3층 | 2927264 | 995 | 0.71242 | 0.0170981 | 716
2931530 | 지상 3층 | 지상 3층 | 2927264 | 995 | 0.63879 | 0.015331 | 642
2931568 | 지상 3층 | 지상 3층 | 2927264 | 995 | 0.729335 | 0.017504 | 733
2931606 | 지상 3층 | 지상 3층 | 2927264 | 995 | 0.907783 | 0.0217868 | 912.345
2936725 | 지상 4층 | 지상 4층 | 2936724 | 1425 | 1.12061 | 0.0268947 | 786.395
3184188 | 지상 4층 | 지상 4층 | 2936724 | 1425 | 1.0203 | 0.0244872 | 716
3184137 | 지상 4층 | 지상 4층 | 2936724 | 1425 | 1.0203 | 0.0244872 | 716
3184054 | 지상 4층 | 지상 4층 | 2936724 | 1425 | 1.0203 | 0.0244872 | 716
3183999 | 지상 4층 | 지상 4층 | 2936724 | 1425 | 1.0203 | 0.0244872 | 716
3183948 | 지상 4층 | 지상 4층 | 2936724 | 1425 | 1.0203 | 0.0244872 | 716
2937119 | 지상 4층 | 지상 4층 | 2936724 | 1425 | 1.0203 | 0.0244872 | 716
2937108 | 지상 4층 | 지상 4층 | 2936724 | 1425 | 1.0203 | 0.0244872 | 716
2937097 | 지상 4층 | 지상 4층 | 2936724 | 1425 | 1.0203 | 0.0244872 | 716
2937086 | 지상 4층 | 지상 4층 | 2936724 | 1425 | 1.0203 | 0.0244872 | 716
2937075 | 지상 4층 | 지상 4층 | 2936724 | 1425 | 1.0203 | 0.0244872 | 716
2937024 | 지상 4층 | 지상 4층 | 2936724 | 1425 | 1.0203 | 0.0244872 | 716
2937035 | 지상 4층 | 지상 4층 | 2936724 | 1425 | 0.91485 | 0.0219564 | 642
2937046 | 지상 4층 | 지상 4층 | 2936724 | 1425 | 1.04453 | 0.0250686 | 733
2937057 | 지상 4층 | 지상 4층 | 2936724 | 1425 | 1.30009 | 0.0312022 | 912.345
2937954 | 지상 4층 | 지상 4층 | 2936724 | 900 | 0.707755 | 0.0169861 | 786.395
3184189 | 지상 4층 | 지상 4층 | 2936724 | 900 | 0.6444 | 0.0154656 | 716
3184138 | 지상 4층 | 지상 4층 | 2936724 | 900 | 0.6444 | 0.0154656 | 716
3184055 | 지상 4층 | 지상 4층 | 2936724 | 900 | 0.6444 | 0.0154656 | 716
3184000 | 지상 4층 | 지상 4층 | 2936724 | 900 | 0.6444 | 0.0154656 | 716
3183949 | 지상 4층 | 지상 4층 | 2936724 | 900 | 0.6444 | 0.0154656 | 716
2937955 | 지상 4층 | 지상 4층 | 2936724 | 900 | 0.6444 | 0.0154656 | 716
2937956 | 지상 4층 | 지상 4층 | 2936724 | 900 | 0.6444 | 0.0154656 | 716
2937957 | 지상 4층 | 지상 4층 | 2936724 | 900 | 0.6444 | 0.0154656 | 716
2937958 | 지상 4층 | 지상 4층 | 2936724 | 900 | 0.6444 | 0.0154656 | 716
2937959 | 지상 4층 | 지상 4층 | 2936724 | 900 | 0.6444 | 0.0154656 | 716
2937960 | 지상 4층 | 지상 4층 | 2936724 | 900 | 0.6444 | 0.0154656 | 716
2937961 | 지상 4층 | 지상 4층 | 2936724 | 900 | 0.5778 | 0.0138672 | 642
2937962 | 지상 4층 | 지상 4층 | 2936724 | 900 | 0.6597 | 0.0158328 | 733
2937963 | 지상 4층 | 지상 4층 | 2936724 | 900 | 0.82111 | 0.0197066 | 912.345
2937058 | 지상 4층 | 지상 4층 | 2936724 | 550 | 0.501789 | 0.0120429 | 912.345
2936731 | 지상 4층 | 지상 4층 | 2936724 | 1025 | 0.806055 | 0.0193453 | 786.395
3184191 | 지상 4층 | 지상 4층 | 2936724 | 1025 | 0.7339 | 0.0176136 | 716
3184140 | 지상 4층 | 지상 4층 | 2936724 | 1025 | 0.7339 | 0.0176136 | 716
3184057 | 지상 4층 | 지상 4층 | 2936724 | 1025 | 0.7339 | 0.0176136 | 716
3184002 | 지상 4층 | 지상 4층 | 2936724 | 1025 | 0.7339 | 0.0176136 | 716
3183951 | 지상 4층 | 지상 4층 | 2936724 | 1025 | 0.7339 | 0.0176136 | 716
2937121 | 지상 4층 | 지상 4층 | 2936724 | 1025 | 0.7339 | 0.0176136 | 716
2937110 | 지상 4층 | 지상 4층 | 2936724 | 1025 | 0.7339 | 0.0176136 | 716
2937099 | 지상 4층 | 지상 4층 | 2936724 | 1025 | 0.7339 | 0.0176136 | 716
2937088 | 지상 4층 | 지상 4층 | 2936724 | 1025 | 0.7339 | 0.0176136 | 716
2937077 | 지상 4층 | 지상 4층 | 2936724 | 1025 | 0.7339 | 0.0176136 | 716
2937026 | 지상 4층 | 지상 4층 | 2936724 | 1025 | 0.7339 | 0.0176136 | 716
2937037 | 지상 4층 | 지상 4층 | 2936724 | 1025 | 0.65805 | 0.0157932 | 642
2937048 | 지상 4층 | 지상 4층 | 2936724 | 1025 | 0.751325 | 0.0180318 | 733
2937059 | 지상 4층 | 지상 4층 | 2936724 | 1025 | 0.935153 | 0.0224437 | 912.345
2938146 | 지상 4층 | 지상 4층 | 2938145 | 325 | 0.0579782 | 0.00139148 | 178.395
2938162 | 지상 4층 | 지상 4층 | 2938145 | 325 | 0.261137 | 0.0062673 | 803.5
2938173 | 지상 4층 | 지상 4층 | 2938145 | 325 | 0.261137 | 0.0062673 | 803.5
2938185 | 지상 4층 | 지상 4층 | 2938145 | 325 | 0.261137 | 0.0062673 | 803.5
2938192 | 지상 4층 | 지상 4층 | 2938145 | 325 | 0.261137 | 0.0062673 | 803.5
2938199 | 지상 4층 | 지상 4층 | 2938145 | 325 | 0.261137 | 0.0062673 | 803.5
2938210 | 지상 4층 | 지상 4층 | 2938145 | 325 | 0.261137 | 0.0062673 | 803.5
2938221 | 지상 4층 | 지상 4층 | 2938145 | 325 | 0.261137 | 0.0062673 | 803.5
2938232 | 지상 4층 | 지상 4층 | 2938145 | 325 | 0.261137 | 0.0062673 | 803.5
2938243 | 지상 4층 | 지상 4층 | 2938145 | 325 | 0.364 | 0.008736 | 1120
2938254 | 지상 4층 | 지상 4층 | 2938145 | 325 | 0.236925 | 0.0056862 | 729
2938265 | 지상 4층 | 지상 4층 | 2938145 | 325 | 0.236925 | 0.0056862 | 729
2938276 | 지상 4층 | 지상 4층 | 2938145 | 325 | 0.236925 | 0.0056862 | 729
2938287 | 지상 4층 | 지상 4층 | 2938145 | 325 | 0.236925 | 0.0056862 | 729
2938298 | 지상 4층 | 지상 4층 | 2938145 | 325 | 0.236925 | 0.0056862 | 729
2938309 | 지상 4층 | 지상 4층 | 2938145 | 325 | 0.236925 | 0.0056862 | 729
2938320 | 지상 4층 | 지상 4층 | 2938145 | 325 | 0.236925 | 0.0056862 | 729
2938331 | 지상 4층 | 지상 4층 | 2938145 | 325 | 0.236925 | 0.0056862 | 729
2938342 | 지상 4층 | 지상 4층 | 2938145 | 325 | 0.364 | 0.008736 | 1120
2938364 | 지상 4층 | 지상 4층 | 2938145 | 325 | 0.232862 | 0.0055887 | 716.5
2938353 | 지상 4층 | 지상 4층 | 2938145 | 325 | 0.232862 | 0.0055887 | 716.5
2938375 | 지상 4층 | 지상 4층 | 2938145 | 325 | 0.232862 | 0.0055887 | 716.5
2938602 | 지상 4층 | 지상 4층 | 2938145 | 325 | 0.232862 | 0.0055887 | 716.5
2938591 | 지상 4층 | 지상 4층 | 2938145 | 325 | 0.232862 | 0.0055887 | 716.5
2938386 | 지상 4층 | 지상 4층 | 2938145 | 325 | 0.232862 | 0.0055887 | 716.5
2938401 | 지상 4층 | 지상 4층 | 2938145 | 325 | 0.232862 | 0.0055887 | 716.5
2938412 | 지상 4층 | 지상 4층 | 2938145 | 325 | 0.232862 | 0.0055887 | 716.5
2938157 | 지상 4층 | 지상 4층 | 2938145 | 550 | 0.098117 | 0.00235481 | 178.395
2938244 | 지상 4층 | 지상 4층 | 2938145 | 550 | 0.616 | 0.014784 | 1120
2938343 | 지상 4층 | 지상 4층 | 2938145 | 550 | 0.616 | 0.014784 | 1120
2938152 | 지상 4층 | 지상 4층 | 2938145 | 1025 | 0.182854 | 0.00438851 | 178.395
2938164 | 지상 4층 | 지상 4층 | 2938145 | 1025 | 0.823588 | 0.0197661 | 803.5
2938175 | 지상 4층 | 지상 4층 | 2938145 | 1025 | 0.823588 | 0.0197661 | 803.5
2938187 | 지상 4층 | 지상 4층 | 2938145 | 1025 | 0.823588 | 0.0197661 | 803.5
2938194 | 지상 4층 | 지상 4층 | 2938145 | 1025 | 0.823588 | 0.0197661 | 803.5
2938201 | 지상 4층 | 지상 4층 | 2938145 | 1025 | 0.823588 | 0.0197661 | 803.5
2938212 | 지상 4층 | 지상 4층 | 2938145 | 1025 | 0.823588 | 0.0197661 | 803.5
2938223 | 지상 4층 | 지상 4층 | 2938145 | 1025 | 0.823588 | 0.0197661 | 803.5
2938234 | 지상 4층 | 지상 4층 | 2938145 | 1025 | 0.823588 | 0.0197661 | 803.5
2938245 | 지상 4층 | 지상 4층 | 2938145 | 1025 | 1.148 | 0.027552 | 1120
2938256 | 지상 4층 | 지상 4층 | 2938145 | 1025 | 0.747225 | 0.0179334 | 729
2938267 | 지상 4층 | 지상 4층 | 2938145 | 1025 | 0.747225 | 0.0179334 | 729
2938278 | 지상 4층 | 지상 4층 | 2938145 | 1025 | 0.747225 | 0.0179334 | 729
2938289 | 지상 4층 | 지상 4층 | 2938145 | 1025 | 0.747225 | 0.0179334 | 729
2938300 | 지상 4층 | 지상 4층 | 2938145 | 1025 | 0.747225 | 0.0179334 | 729
2938311 | 지상 4층 | 지상 4층 | 2938145 | 1025 | 0.747225 | 0.0179334 | 729
2938322 | 지상 4층 | 지상 4층 | 2938145 | 1025 | 0.747225 | 0.0179334 | 729
2938333 | 지상 4층 | 지상 4층 | 2938145 | 1025 | 0.747225 | 0.0179334 | 729
2938344 | 지상 4층 | 지상 4층 | 2938145 | 1025 | 1.148 | 0.027552 | 1120
2938366 | 지상 4층 | 지상 4층 | 2938145 | 1025 | 0.734412 | 0.0176259 | 716.5
2938355 | 지상 4층 | 지상 4층 | 2938145 | 1025 | 0.734412 | 0.0176259 | 716.5
2938377 | 지상 4층 | 지상 4층 | 2938145 | 1025 | 0.734412 | 0.0176259 | 716.5
2938604 | 지상 4층 | 지상 4층 | 2938145 | 1025 | 0.734412 | 0.0176259 | 716.5
2938593 | 지상 4층 | 지상 4층 | 2938145 | 1025 | 0.734412 | 0.0176259 | 716.5
2938388 | 지상 4층 | 지상 4층 | 2938145 | 1025 | 0.734412 | 0.0176259 | 716.5
2938403 | 지상 4층 | 지상 4층 | 2938145 | 1025 | 0.734412 | 0.0176259 | 716.5
2938414 | 지상 4층 | 지상 4층 | 2938145 | 1025 | 0.734412 | 0.0176259 | 716.5
2940511 | 지상 3층 | 지상 3층 | 2940510 | 875 | 0.798168 | 0.019156 | 912.192
2941413 | 지상 3층 | 지상 3층 | 2940510 | 875 | 0.826875 | 0.019845 | 945
2941767 | 지상 3층 | 지상 3층 | 2940510 | 875 | 0.800625 | 0.019215 | 915
2941814 | 지상 3층 | 지상 3층 | 2940510 | 875 | 0.800625 | 0.019215 | 915
2941939 | 지상 3층 | 지상 3층 | 2940510 | 875 | 0.800625 | 0.019215 | 915
2941984 | 지상 3층 | 지상 3층 | 2940510 | 875 | 0.800625 | 0.019215 | 915
2942029 | 지상 3층 | 지상 3층 | 2940510 | 875 | 0.800625 | 0.019215 | 915
2942074 | 지상 3층 | 지상 3층 | 2940510 | 875 | 0.800625 | 0.019215 | 915
2942119 | 지상 3층 | 지상 3층 | 2940510 | 875 | 0.800625 | 0.019215 | 915
2942162 | 지상 3층 | 지상 3층 | 2940510 | 875 | 0.800625 | 0.019215 | 915
2942330 | 지상 3층 | 지상 3층 | 2940510 | 875 | 0.800625 | 0.019215 | 915
2942375 | 지상 3층 | 지상 3층 | 2940510 | 875 | 0.800625 | 0.019215 | 915
2942654 | 지상 3층 | 지상 3층 | 2940510 | 875 | 0.826875 | 0.019845 | 945
2942699 | 지상 3층 | 지상 3층 | 2940510 | 875 | 0.88375 | 0.02121 | 1010
2942968 | 지상 3층 | 지상 3층 | 2940510 | 875 | 0.93625 | 0.02247 | 1070
2942972 | 지상 3층 | 지상 3층 | 2940510 | 875 | 0.93625 | 0.02247 | 1070
2942976 | 지상 3층 | 지상 3층 | 2940510 | 875 | 0.88375 | 0.02121 | 1010
2942980 | 지상 3층 | 지상 3층 | 2940510 | 875 | 0.800625 | 0.019215 | 915
2942984 | 지상 3층 | 지상 3층 | 2940510 | 875 | 0.800625 | 0.019215 | 915
2942988 | 지상 3층 | 지상 3층 | 2940510 | 875 | 0.800625 | 0.019215 | 915
2942992 | 지상 3층 | 지상 3층 | 2940510 | 875 | 0.800625 | 0.019215 | 915
2942996 | 지상 3층 | 지상 3층 | 2940510 | 875 | 0.800625 | 0.019215 | 915
2943000 | 지상 3층 | 지상 3층 | 2940510 | 875 | 0.800625 | 0.019215 | 915
2943004 | 지상 3층 | 지상 3층 | 2940510 | 875 | 0.800625 | 0.019215 | 915
2943008 | 지상 3층 | 지상 3층 | 2940510 | 875 | 0.800625 | 0.019215 | 915
2943012 | 지상 3층 | 지상 3층 | 2940510 | 875 | 0.800625 | 0.019215 | 915
2943016 | 지상 3층 | 지상 3층 | 2940510 | 875 | 0.79625 | 0.01911 | 910
2943734 | 지상 3층 | 지상 3층 | 2940510 | 875 | 0.88375 | 0.02121 | 1010
2943196 | 지상 3층 | 지상 3층 | 2940510 | 875 | 0.84875 | 0.02037 | 970
2943200 | 지상 3층 | 지상 3층 | 2940510 | 875 | 0.800625 | 0.019215 | 915
2943204 | 지상 3층 | 지상 3층 | 2940510 | 875 | 0.800625 | 0.019215 | 915
2943208 | 지상 3층 | 지상 3층 | 2940510 | 875 | 0.800625 | 0.019215 | 915
2943212 | 지상 3층 | 지상 3층 | 2940510 | 875 | 0.800625 | 0.019215 | 915
2943216 | 지상 3층 | 지상 3층 | 2940510 | 875 | 0.800625 | 0.019215 | 915
2943220 | 지상 3층 | 지상 3층 | 2940510 | 875 | 0.800625 | 0.019215 | 915
2943224 | 지상 3층 | 지상 3층 | 2940510 | 875 | 0.800625 | 0.019215 | 915
2943228 | 지상 3층 | 지상 3층 | 2940510 | 875 | 0.888125 | 0.021315 | 1015
2943232 | 지상 3층 | 지상 3층 | 2940510 | 875 | 0.781207 | 0.018749 | 892.808
2941462 | 지상 3층 | 지상 3층 | 2940510 | 550 | 0.501706 | 0.0120409 | 912.192
2942700 | 지상 3층 | 지상 3층 | 2940510 | 550 | 0.5555 | 0.013332 | 1010
2942977 | 지상 3층 | 지상 3층 | 2940510 | 550 | 0.5555 | 0.013332 | 1010
2943735 | 지상 3층 | 지상 3층 | 2940510 | 550 | 0.5555 | 0.013332 | 1010
2943233 | 지상 3층 | 지상 3층 | 2940510 | 550 | 0.491044 | 0.0117851 | 892.808
2941520 | 지상 3층 | 지상 3층 | 2940510 | 1020 | 0.930436 | 0.0223305 | 912.192
2941521 | 지상 3층 | 지상 3층 | 2940510 | 1020 | 0.9639 | 0.0231336 | 945
2941769 | 지상 3층 | 지상 3층 | 2940510 | 1020 | 0.9333 | 0.0223992 | 915
2941816 | 지상 3층 | 지상 3층 | 2940510 | 1020 | 0.9333 | 0.0223992 | 915
2941941 | 지상 3층 | 지상 3층 | 2940510 | 1020 | 0.9333 | 0.0223992 | 915
2941986 | 지상 3층 | 지상 3층 | 2940510 | 1020 | 0.9333 | 0.0223992 | 915
2942031 | 지상 3층 | 지상 3층 | 2940510 | 1020 | 0.9333 | 0.0223992 | 915
2942076 | 지상 3층 | 지상 3층 | 2940510 | 1020 | 0.9333 | 0.0223992 | 915
2942121 | 지상 3층 | 지상 3층 | 2940510 | 1020 | 0.9333 | 0.0223992 | 915
2942164 | 지상 3층 | 지상 3층 | 2940510 | 1020 | 0.9333 | 0.0223992 | 915
2942332 | 지상 3층 | 지상 3층 | 2940510 | 1020 | 0.9333 | 0.0223992 | 915
2942377 | 지상 3층 | 지상 3층 | 2940510 | 1020 | 0.9333 | 0.0223992 | 915
2942656 | 지상 3층 | 지상 3층 | 2940510 | 1020 | 0.9639 | 0.0231336 | 945
2942701 | 지상 3층 | 지상 3층 | 2940510 | 1020 | 1.0302 | 0.0247248 | 1010
2942970 | 지상 3층 | 지상 3층 | 2940510 | 1020 | 1.0914 | 0.0261936 | 1070
2942974 | 지상 3층 | 지상 3층 | 2940510 | 1020 | 1.0914 | 0.0261936 | 1070
2942978 | 지상 3층 | 지상 3층 | 2940510 | 1020 | 1.0302 | 0.0247248 | 1010
2942982 | 지상 3층 | 지상 3층 | 2940510 | 1020 | 0.9333 | 0.0223992 | 915
2942986 | 지상 3층 | 지상 3층 | 2940510 | 1020 | 0.9333 | 0.0223992 | 915
2942990 | 지상 3층 | 지상 3층 | 2940510 | 1020 | 0.9333 | 0.0223992 | 915
2942994 | 지상 3층 | 지상 3층 | 2940510 | 1020 | 0.9333 | 0.0223992 | 915
2942998 | 지상 3층 | 지상 3층 | 2940510 | 1020 | 0.9333 | 0.0223992 | 915
2943002 | 지상 3층 | 지상 3층 | 2940510 | 1020 | 0.9333 | 0.0223992 | 915
2943006 | 지상 3층 | 지상 3층 | 2940510 | 1020 | 0.9333 | 0.0223992 | 915
2943010 | 지상 3층 | 지상 3층 | 2940510 | 1020 | 0.9333 | 0.0223992 | 915
2943014 | 지상 3층 | 지상 3층 | 2940510 | 1020 | 0.9333 | 0.0223992 | 915
2943018 | 지상 3층 | 지상 3층 | 2940510 | 1020 | 0.9282 | 0.0222768 | 910
2943736 | 지상 3층 | 지상 3층 | 2940510 | 1020 | 1.0302 | 0.0247248 | 1010
2943198 | 지상 3층 | 지상 3층 | 2940510 | 1020 | 0.9894 | 0.0237456 | 970
2943202 | 지상 3층 | 지상 3층 | 2940510 | 1020 | 0.9333 | 0.0223992 | 915
2943206 | 지상 3층 | 지상 3층 | 2940510 | 1020 | 0.9333 | 0.0223992 | 915
2943210 | 지상 3층 | 지상 3층 | 2940510 | 1020 | 0.9333 | 0.0223992 | 915
2943214 | 지상 3층 | 지상 3층 | 2940510 | 1020 | 0.9333 | 0.0223992 | 915
2943218 | 지상 3층 | 지상 3층 | 2940510 | 1020 | 0.9333 | 0.0223992 | 915
2943222 | 지상 3층 | 지상 3층 | 2940510 | 1020 | 0.9333 | 0.0223992 | 915
2943226 | 지상 3층 | 지상 3층 | 2940510 | 1020 | 0.9333 | 0.0223992 | 915
2943230 | 지상 3층 | 지상 3층 | 2940510 | 1020 | 1.0353 | 0.0248472 | 1015
2943234 | 지상 3층 | 지상 3층 | 2940510 | 1020 | 0.910664 | 0.0218559 | 892.808
2941578 | 지상 3층 | 지상 3층 | 2940510 | 1405 | 1.28163 | 0.0307591 | 912.192
2941579 | 지상 3층 | 지상 3층 | 2940510 | 1405 | 1.32773 | 0.0318654 | 945
2941770 | 지상 3층 | 지상 3층 | 2940510 | 1405 | 1.28557 | 0.0308538 | 915
2941817 | 지상 3층 | 지상 3층 | 2940510 | 1405 | 1.28557 | 0.0308538 | 915
2941942 | 지상 3층 | 지상 3층 | 2940510 | 1405 | 1.28557 | 0.0308538 | 915
2941987 | 지상 3층 | 지상 3층 | 2940510 | 1405 | 1.28557 | 0.0308538 | 915
2942032 | 지상 3층 | 지상 3층 | 2940510 | 1405 | 1.28557 | 0.0308538 | 915
2942077 | 지상 3층 | 지상 3층 | 2940510 | 1405 | 1.28557 | 0.0308538 | 915
2942122 | 지상 3층 | 지상 3층 | 2940510 | 1405 | 1.28557 | 0.0308538 | 915
2942165 | 지상 3층 | 지상 3층 | 2940510 | 1405 | 1.28557 | 0.0308538 | 915
2942333 | 지상 3층 | 지상 3층 | 2940510 | 1405 | 1.28557 | 0.0308538 | 915
2942378 | 지상 3층 | 지상 3층 | 2940510 | 1405 | 1.28557 | 0.0308538 | 915
2942657 | 지상 3층 | 지상 3층 | 2940510 | 1405 | 1.32773 | 0.0318654 | 945
2942702 | 지상 3층 | 지상 3층 | 2940510 | 1405 | 1.41905 | 0.0340572 | 1010
2942971 | 지상 3층 | 지상 3층 | 2940510 | 1405 | 1.50335 | 0.0360804 | 1070
2942975 | 지상 3층 | 지상 3층 | 2940510 | 1405 | 1.50335 | 0.0360804 | 1070
2942979 | 지상 3층 | 지상 3층 | 2940510 | 1405 | 1.41905 | 0.0340572 | 1010
2942983 | 지상 3층 | 지상 3층 | 2940510 | 1405 | 1.28557 | 0.0308538 | 915
2942987 | 지상 3층 | 지상 3층 | 2940510 | 1405 | 1.28557 | 0.0308538 | 915
2942991 | 지상 3층 | 지상 3층 | 2940510 | 1405 | 1.28557 | 0.0308538 | 915
2942995 | 지상 3층 | 지상 3층 | 2940510 | 1405 | 1.28557 | 0.0308538 | 915
2942999 | 지상 3층 | 지상 3층 | 2940510 | 1405 | 1.28557 | 0.0308538 | 915
2943003 | 지상 3층 | 지상 3층 | 2940510 | 1405 | 1.28557 | 0.0308538 | 915
2943007 | 지상 3층 | 지상 3층 | 2940510 | 1405 | 1.28557 | 0.0308538 | 915
2943011 | 지상 3층 | 지상 3층 | 2940510 | 1405 | 1.28557 | 0.0308538 | 915
2943015 | 지상 3층 | 지상 3층 | 2940510 | 1405 | 1.28557 | 0.0308538 | 915
2943019 | 지상 3층 | 지상 3층 | 2940510 | 1405 | 1.27855 | 0.0306852 | 910
2943737 | 지상 3층 | 지상 3층 | 2940510 | 1405 | 1.41905 | 0.0340572 | 1010
2943199 | 지상 3층 | 지상 3층 | 2940510 | 1405 | 1.36285 | 0.0327084 | 970
2943203 | 지상 3층 | 지상 3층 | 2940510 | 1405 | 1.28557 | 0.0308538 | 915
2943207 | 지상 3층 | 지상 3층 | 2940510 | 1405 | 1.28557 | 0.0308538 | 915
2943211 | 지상 3층 | 지상 3층 | 2940510 | 1405 | 1.28557 | 0.0308538 | 915
2943215 | 지상 3층 | 지상 3층 | 2940510 | 1405 | 1.28557 | 0.0308538 | 915
2943219 | 지상 3층 | 지상 3층 | 2940510 | 1405 | 1.28557 | 0.0308538 | 915
2943223 | 지상 3층 | 지상 3층 | 2940510 | 1405 | 1.28557 | 0.0308538 | 915
2943227 | 지상 3층 | 지상 3층 | 2940510 | 1405 | 1.28557 | 0.0308538 | 915
2943231 | 지상 3층 | 지상 3층 | 2940510 | 1405 | 1.42607 | 0.0342258 | 1015
2943235 | 지상 3층 | 지상 3층 | 2940510 | 1405 | 1.25439 | 0.0301055 | 892.808
2944601 | 지상 4층 | 지상 4층 | 2944600 | 895 | 0.816971 | 0.0196073 | 912.816
2944607 | 지상 4층 | 지상 4층 | 2944600 | 895 | 0.845775 | 0.0202986 | 945
2944636 | 지상 4층 | 지상 4층 | 2944600 | 895 | 0.818925 | 0.0196542 | 915
2944650 | 지상 4층 | 지상 4층 | 2944600 | 895 | 0.818925 | 0.0196542 | 915
2944664 | 지상 4층 | 지상 4층 | 2944600 | 895 | 0.818925 | 0.0196542 | 915
2944678 | 지상 4층 | 지상 4층 | 2944600 | 895 | 0.818925 | 0.0196542 | 915
2944692 | 지상 4층 | 지상 4층 | 2944600 | 895 | 0.818925 | 0.0196542 | 915
2944706 | 지상 4층 | 지상 4층 | 2944600 | 895 | 0.818925 | 0.0196542 | 915
2944720 | 지상 4층 | 지상 4층 | 2944600 | 895 | 0.818925 | 0.0196542 | 915
2944734 | 지상 4층 | 지상 4층 | 2944600 | 895 | 0.818925 | 0.0196542 | 915
2944748 | 지상 4층 | 지상 4층 | 2944600 | 895 | 0.818925 | 0.0196542 | 915
2944762 | 지상 4층 | 지상 4층 | 2944600 | 895 | 0.818925 | 0.0196542 | 915
2944776 | 지상 4층 | 지상 4층 | 2944600 | 895 | 0.845775 | 0.0202986 | 945
2944790 | 지상 4층 | 지상 4층 | 2944600 | 895 | 0.90395 | 0.0216948 | 1010
2944816 | 지상 4층 | 지상 4층 | 2944600 | 895 | 0.95765 | 0.0229836 | 1070
2944820 | 지상 4층 | 지상 4층 | 2944600 | 895 | 0.95765 | 0.0229836 | 1070
2944824 | 지상 4층 | 지상 4층 | 2944600 | 895 | 0.90395 | 0.0216948 | 1010
2944828 | 지상 4층 | 지상 4층 | 2944600 | 895 | 0.818925 | 0.0196542 | 915
2944832 | 지상 4층 | 지상 4층 | 2944600 | 895 | 0.818925 | 0.0196542 | 915
2944836 | 지상 4층 | 지상 4층 | 2944600 | 895 | 0.818925 | 0.0196542 | 915
2944840 | 지상 4층 | 지상 4층 | 2944600 | 895 | 0.818925 | 0.0196542 | 915
2944844 | 지상 4층 | 지상 4층 | 2944600 | 895 | 0.818925 | 0.0196542 | 915
2944848 | 지상 4층 | 지상 4층 | 2944600 | 895 | 0.818925 | 0.0196542 | 915
2944852 | 지상 4층 | 지상 4층 | 2944600 | 895 | 0.818925 | 0.0196542 | 915
2944856 | 지상 4층 | 지상 4층 | 2944600 | 895 | 0.818925 | 0.0196542 | 915
2944860 | 지상 4층 | 지상 4층 | 2944600 | 895 | 0.818925 | 0.0196542 | 915
2944864 | 지상 4층 | 지상 4층 | 2944600 | 895 | 0.81445 | 0.0195468 | 910
2945126 | 지상 4층 | 지상 4층 | 2944600 | 895 | 0.90395 | 0.0216948 | 1010
2944995 | 지상 4층 | 지상 4층 | 2944600 | 895 | 0.86815 | 0.0208356 | 970
2944999 | 지상 4층 | 지상 4층 | 2944600 | 895 | 0.818925 | 0.0196542 | 915
2945003 | 지상 4층 | 지상 4층 | 2944600 | 895 | 0.818925 | 0.0196542 | 915
2945007 | 지상 4층 | 지상 4층 | 2944600 | 895 | 0.818925 | 0.0196542 | 915
2945011 | 지상 4층 | 지상 4층 | 2944600 | 895 | 0.818925 | 0.0196542 | 915
2945015 | 지상 4층 | 지상 4층 | 2944600 | 895 | 0.818925 | 0.0196542 | 915
2945019 | 지상 4층 | 지상 4층 | 2944600 | 895 | 0.818925 | 0.0196542 | 915
2945023 | 지상 4층 | 지상 4층 | 2944600 | 895 | 0.818925 | 0.0196542 | 915
2945027 | 지상 4층 | 지상 4층 | 2944600 | 895 | 0.908425 | 0.0218022 | 1015
2945031 | 지상 4층 | 지상 4층 | 2944600 | 895 | 0.799063 | 0.0191775 | 892.808
2944612 | 지상 4층 | 지상 4층 | 2944600 | 550 | 0.502049 | 0.0120492 | 912.816
2944791 | 지상 4층 | 지상 4층 | 2944600 | 550 | 0.5555 | 0.013332 | 1010
2944825 | 지상 4층 | 지상 4층 | 2944600 | 550 | 0.5555 | 0.013332 | 1010
2945127 | 지상 4층 | 지상 4층 | 2944600 | 550 | 0.5555 | 0.013332 | 1010
2945032 | 지상 4층 | 지상 4층 | 2944600 | 550 | 0.491044 | 0.0117851 | 892.808
2944620 | 지상 4층 | 지상 4층 | 2944600 | 1025 | 0.935637 | 0.0224553 | 912.816
2944621 | 지상 4층 | 지상 4층 | 2944600 | 1025 | 0.968625 | 0.023247 | 945
2944638 | 지상 4층 | 지상 4층 | 2944600 | 1025 | 0.937875 | 0.022509 | 915
2944652 | 지상 4층 | 지상 4층 | 2944600 | 1025 | 0.937875 | 0.022509 | 915
2944666 | 지상 4층 | 지상 4층 | 2944600 | 1025 | 0.937875 | 0.022509 | 915
2944680 | 지상 4층 | 지상 4층 | 2944600 | 1025 | 0.937875 | 0.022509 | 915
2944694 | 지상 4층 | 지상 4층 | 2944600 | 1025 | 0.937875 | 0.022509 | 915
2944708 | 지상 4층 | 지상 4층 | 2944600 | 1025 | 0.937875 | 0.022509 | 915
2944722 | 지상 4층 | 지상 4층 | 2944600 | 1025 | 0.937875 | 0.022509 | 915
2944736 | 지상 4층 | 지상 4층 | 2944600 | 1025 | 0.937875 | 0.022509 | 915
2944750 | 지상 4층 | 지상 4층 | 2944600 | 1025 | 0.937875 | 0.022509 | 915
2944764 | 지상 4층 | 지상 4층 | 2944600 | 1025 | 0.937875 | 0.022509 | 915
2944778 | 지상 4층 | 지상 4층 | 2944600 | 1025 | 0.968625 | 0.023247 | 945
2944792 | 지상 4층 | 지상 4층 | 2944600 | 1025 | 1.03525 | 0.024846 | 1010
2944818 | 지상 4층 | 지상 4층 | 2944600 | 1025 | 1.09675 | 0.026322 | 1070
2944822 | 지상 4층 | 지상 4층 | 2944600 | 1025 | 1.09675 | 0.026322 | 1070
2944826 | 지상 4층 | 지상 4층 | 2944600 | 1025 | 1.03525 | 0.024846 | 1010
2944830 | 지상 4층 | 지상 4층 | 2944600 | 1025 | 0.937875 | 0.022509 | 915
2944834 | 지상 4층 | 지상 4층 | 2944600 | 1025 | 0.937875 | 0.022509 | 915
2944838 | 지상 4층 | 지상 4층 | 2944600 | 1025 | 0.937875 | 0.022509 | 915
2944842 | 지상 4층 | 지상 4층 | 2944600 | 1025 | 0.937875 | 0.022509 | 915
2944846 | 지상 4층 | 지상 4층 | 2944600 | 1025 | 0.937875 | 0.022509 | 915
2944850 | 지상 4층 | 지상 4층 | 2944600 | 1025 | 0.937875 | 0.022509 | 915
2944854 | 지상 4층 | 지상 4층 | 2944600 | 1025 | 0.937875 | 0.022509 | 915
2944858 | 지상 4층 | 지상 4층 | 2944600 | 1025 | 0.937875 | 0.022509 | 915
2944862 | 지상 4층 | 지상 4층 | 2944600 | 1025 | 0.937875 | 0.022509 | 915
2944866 | 지상 4층 | 지상 4층 | 2944600 | 1025 | 0.93275 | 0.022386 | 910
2945128 | 지상 4층 | 지상 4층 | 2944600 | 1025 | 1.03525 | 0.024846 | 1010
2944997 | 지상 4층 | 지상 4층 | 2944600 | 1025 | 0.99425 | 0.023862 | 970
2945001 | 지상 4층 | 지상 4층 | 2944600 | 1025 | 0.937875 | 0.022509 | 915
2945005 | 지상 4층 | 지상 4층 | 2944600 | 1025 | 0.937875 | 0.022509 | 915
2945009 | 지상 4층 | 지상 4층 | 2944600 | 1025 | 0.937875 | 0.022509 | 915
2945013 | 지상 4층 | 지상 4층 | 2944600 | 1025 | 0.937875 | 0.022509 | 915
2945017 | 지상 4층 | 지상 4층 | 2944600 | 1025 | 0.937875 | 0.022509 | 915
2945021 | 지상 4층 | 지상 4층 | 2944600 | 1025 | 0.937875 | 0.022509 | 915
2945025 | 지상 4층 | 지상 4층 | 2944600 | 1025 | 0.937875 | 0.022509 | 915
2945029 | 지상 4층 | 지상 4층 | 2944600 | 1025 | 1.04038 | 0.024969 | 1015
2945033 | 지상 4층 | 지상 4층 | 2944600 | 1025 | 0.915128 | 0.0219631 | 892.808
2945776 | 지상 3층 | 지상 3층 | 2945775 | 875 | 0.68547 | 0.0164513 | 783.395
2945873 | 지상 3층 | 지상 3층 | 2945775 | 875 | 0.6125 | 0.0147 | 700
2945884 | 지상 3층 | 지상 3층 | 2945775 | 875 | 0.637875 | 0.015309 | 729
2947767 | 지상 3층 | 지상 3층 | 2945775 | 875 | 0.637875 | 0.015309 | 729
2945895 | 지상 3층 | 지상 3층 | 2945775 | 875 | 0.637875 | 0.015309 | 729
2945906 | 지상 3층 | 지상 3층 | 2945775 | 875 | 0.637875 | 0.015309 | 729
2945917 | 지상 3층 | 지상 3층 | 2945775 | 875 | 0.637875 | 0.015309 | 729
2945928 | 지상 3층 | 지상 3층 | 2945775 | 875 | 0.637875 | 0.015309 | 729
2945939 | 지상 3층 | 지상 3층 | 2945775 | 875 | 0.637875 | 0.015309 | 729
2945950 | 지상 3층 | 지상 3층 | 2945775 | 875 | 0.690375 | 0.016569 | 789
2945972 | 지상 3층 | 지상 3층 | 2945775 | 875 | 0.875 | 0.021 | 1000
2945994 | 지상 3층 | 지상 3층 | 2945775 | 875 | 0.679 | 0.016296 | 776
2947249 | 지상 3층 | 지상 3층 | 2945775 | 875 | 0.6265 | 0.015036 | 716
2945983 | 지상 3층 | 지상 3층 | 2945775 | 875 | 0.6265 | 0.015036 | 716
2946005 | 지상 3층 | 지상 3층 | 2945775 | 875 | 0.6265 | 0.015036 | 716
2946232 | 지상 3층 | 지상 3층 | 2945775 | 875 | 0.6265 | 0.015036 | 716
2946221 | 지상 3층 | 지상 3층 | 2945775 | 875 | 0.6265 | 0.015036 | 716
2946016 | 지상 3층 | 지상 3층 | 2945775 | 875 | 0.6265 | 0.015036 | 716
2946031 | 지상 3층 | 지상 3층 | 2945775 | 875 | 0.679 | 0.016296 | 776
2946243 | 지상 3층 | 지상 3층 | 2945775 | 875 | 0.875 | 0.021 | 1000
2946053 | 지상 3층 | 지상 3층 | 2945775 | 875 | 0.679 | 0.016296 | 776
2946691 | 지상 3층 | 지상 3층 | 2945775 | 875 | 0.6265 | 0.015036 | 716
2946652 | 지상 3층 | 지상 3층 | 2945775 | 875 | 0.6265 | 0.015036 | 716
2946064 | 지상 3층 | 지상 3층 | 2945775 | 875 | 0.6265 | 0.015036 | 716
2946210 | 지상 3층 | 지상 3층 | 2945775 | 875 | 0.6265 | 0.015036 | 716
2946199 | 지상 3층 | 지상 3층 | 2945775 | 875 | 0.6265 | 0.015036 | 716
2946188 | 지상 3층 | 지상 3층 | 2945775 | 875 | 0.6265 | 0.015036 | 716
2946181 | 지상 3층 | 지상 3층 | 2945775 | 875 | 0.6265 | 0.015036 | 716
2946170 | 지상 3층 | 지상 3층 | 2945775 | 875 | 0.6265 | 0.015036 | 716
2946159 | 지상 3층 | 지상 3층 | 2945775 | 875 | 0.6265 | 0.015036 | 716
2946148 | 지상 3층 | 지상 3층 | 2945775 | 875 | 0.6265 | 0.015036 | 716
2946075 | 지상 3층 | 지상 3층 | 2945775 | 875 | 0.6265 | 0.015036 | 716
2946086 | 지상 3층 | 지상 3층 | 2945775 | 875 | 0.56175 | 0.013482 | 642
2946097 | 지상 3층 | 지상 3층 | 2945775 | 875 | 0.61425 | 0.014742 | 702
2946108 | 지상 3층 | 지상 3층 | 2945775 | 875 | 0.79853 | 0.0191647 | 912.605
2945973 | 지상 3층 | 지상 3층 | 2945775 | 550 | 0.55 | 0.0132 | 1000
2946244 | 지상 3층 | 지상 3층 | 2945775 | 550 | 0.55 | 0.0132 | 1000
2946109 | 지상 3층 | 지상 3층 | 2945775 | 550 | 0.501933 | 0.0120464 | 912.605
2945782 | 지상 3층 | 지상 3층 | 2945775 | 995 | 0.779478 | 0.0187075 | 783.395
2945875 | 지상 3층 | 지상 3층 | 2945775 | 995 | 0.6965 | 0.016716 | 700
2945886 | 지상 3층 | 지상 3층 | 2945775 | 995 | 0.725355 | 0.0174085 | 729
2947769 | 지상 3층 | 지상 3층 | 2945775 | 995 | 0.725355 | 0.0174085 | 729
2945897 | 지상 3층 | 지상 3층 | 2945775 | 995 | 0.725355 | 0.0174085 | 729
2945908 | 지상 3층 | 지상 3층 | 2945775 | 995 | 0.725355 | 0.0174085 | 729
2945919 | 지상 3층 | 지상 3층 | 2945775 | 995 | 0.725355 | 0.0174085 | 729
2945930 | 지상 3층 | 지상 3층 | 2945775 | 995 | 0.725355 | 0.0174085 | 729
2945941 | 지상 3층 | 지상 3층 | 2945775 | 995 | 0.725355 | 0.0174085 | 729
2945952 | 지상 3층 | 지상 3층 | 2945775 | 995 | 0.785055 | 0.0188413 | 789
2945974 | 지상 3층 | 지상 3층 | 2945775 | 995 | 0.995 | 0.02388 | 1000
2945996 | 지상 3층 | 지상 3층 | 2945775 | 995 | 0.77212 | 0.0185309 | 776
2947251 | 지상 3층 | 지상 3층 | 2945775 | 995 | 0.71242 | 0.0170981 | 716
2945985 | 지상 3층 | 지상 3층 | 2945775 | 995 | 0.71242 | 0.0170981 | 716
2946007 | 지상 3층 | 지상 3층 | 2945775 | 995 | 0.71242 | 0.0170981 | 716
2946234 | 지상 3층 | 지상 3층 | 2945775 | 995 | 0.71242 | 0.0170981 | 716
2946223 | 지상 3층 | 지상 3층 | 2945775 | 995 | 0.71242 | 0.0170981 | 716
2946018 | 지상 3층 | 지상 3층 | 2945775 | 995 | 0.71242 | 0.0170981 | 716
2946033 | 지상 3층 | 지상 3층 | 2945775 | 995 | 0.77212 | 0.0185309 | 776
2946245 | 지상 3층 | 지상 3층 | 2945775 | 995 | 0.995 | 0.02388 | 1000
2946055 | 지상 3층 | 지상 3층 | 2945775 | 995 | 0.77212 | 0.0185309 | 776
2946693 | 지상 3층 | 지상 3층 | 2945775 | 995 | 0.71242 | 0.0170981 | 716
2946654 | 지상 3층 | 지상 3층 | 2945775 | 995 | 0.71242 | 0.0170981 | 716
2946066 | 지상 3층 | 지상 3층 | 2945775 | 995 | 0.71242 | 0.0170981 | 716
2946212 | 지상 3층 | 지상 3층 | 2945775 | 995 | 0.71242 | 0.0170981 | 716
2946201 | 지상 3층 | 지상 3층 | 2945775 | 995 | 0.71242 | 0.0170981 | 716
2946190 | 지상 3층 | 지상 3층 | 2945775 | 995 | 0.71242 | 0.0170981 | 716
2946183 | 지상 3층 | 지상 3층 | 2945775 | 995 | 0.71242 | 0.0170981 | 716
2946172 | 지상 3층 | 지상 3층 | 2945775 | 995 | 0.71242 | 0.0170981 | 716
2946161 | 지상 3층 | 지상 3층 | 2945775 | 995 | 0.71242 | 0.0170981 | 716
2946150 | 지상 3층 | 지상 3층 | 2945775 | 995 | 0.71242 | 0.0170981 | 716
2946077 | 지상 3층 | 지상 3층 | 2945775 | 995 | 0.71242 | 0.0170981 | 716
2946088 | 지상 3층 | 지상 3층 | 2945775 | 995 | 0.63879 | 0.015331 | 642
2946099 | 지상 3층 | 지상 3층 | 2945775 | 995 | 0.69849 | 0.0167638 | 702
2946110 | 지상 3층 | 지상 3층 | 2945775 | 995 | 0.908042 | 0.021793 | 912.605
2948717 | 지상 4층 | 지상 4층 | 2948716 | 1425 | 1.17191 | 0.0281259 | 822.395
3189848 | 지상 4층 | 지상 4층 | 2948716 | 1425 | 1.0203 | 0.0244872 | 716
3189791 | 지상 4층 | 지상 4층 | 2948716 | 1425 | 1.0203 | 0.0244872 | 716
3189729 | 지상 4층 | 지상 4층 | 2948716 | 1425 | 1.0203 | 0.0244872 | 716
2949017 | 지상 4층 | 지상 4층 | 2948716 | 1425 | 1.0203 | 0.0244872 | 716
2949006 | 지상 4층 | 지상 4층 | 2948716 | 1425 | 1.0203 | 0.0244872 | 716
2948995 | 지상 4층 | 지상 4층 | 2948716 | 1425 | 1.0203 | 0.0244872 | 716
2948988 | 지상 4층 | 지상 4층 | 2948716 | 1425 | 1.0203 | 0.0244872 | 716
2948977 | 지상 4층 | 지상 4층 | 2948716 | 1425 | 1.0203 | 0.0244872 | 716
2948966 | 지상 4층 | 지상 4층 | 2948716 | 1425 | 1.0203 | 0.0244872 | 716
2948955 | 지상 4층 | 지상 4층 | 2948716 | 1425 | 1.0203 | 0.0244872 | 716
2948911 | 지상 4층 | 지상 4층 | 2948716 | 1425 | 1.0203 | 0.0244872 | 716
2948922 | 지상 4층 | 지상 4층 | 2948716 | 1425 | 0.91485 | 0.0219564 | 642
2948933 | 지상 4층 | 지상 4층 | 2948716 | 1425 | 1.00035 | 0.0240084 | 702
2948944 | 지상 4층 | 지상 4층 | 2948716 | 1425 | 1.29334 | 0.0310401 | 907.605
2949746 | 지상 4층 | 지상 4층 | 2948716 | 950 | 0.781275 | 0.0187506 | 822.395
3189849 | 지상 4층 | 지상 4층 | 2948716 | 950 | 0.6802 | 0.0163248 | 716
3189792 | 지상 4층 | 지상 4층 | 2948716 | 950 | 0.6802 | 0.0163248 | 716
3189730 | 지상 4층 | 지상 4층 | 2948716 | 950 | 0.6802 | 0.0163248 | 716
2949747 | 지상 4층 | 지상 4층 | 2948716 | 950 | 0.6802 | 0.0163248 | 716
2949748 | 지상 4층 | 지상 4층 | 2948716 | 950 | 0.6802 | 0.0163248 | 716
2949749 | 지상 4층 | 지상 4층 | 2948716 | 950 | 0.6802 | 0.0163248 | 716
2949750 | 지상 4층 | 지상 4층 | 2948716 | 950 | 0.6802 | 0.0163248 | 716
2949751 | 지상 4층 | 지상 4층 | 2948716 | 950 | 0.6802 | 0.0163248 | 716
2949752 | 지상 4층 | 지상 4층 | 2948716 | 950 | 0.6802 | 0.0163248 | 716
2949753 | 지상 4층 | 지상 4층 | 2948716 | 950 | 0.6802 | 0.0163248 | 716
2949754 | 지상 4층 | 지상 4층 | 2948716 | 950 | 0.6802 | 0.0163248 | 716
2949755 | 지상 4층 | 지상 4층 | 2948716 | 950 | 0.6099 | 0.0146376 | 642
2949756 | 지상 4층 | 지상 4층 | 2948716 | 950 | 0.6669 | 0.0160056 | 702
2949757 | 지상 4층 | 지상 4층 | 2948716 | 950 | 0.862225 | 0.0206934 | 907.605
2948945 | 지상 4층 | 지상 4층 | 2948716 | 550 | 0.499183 | 0.0119804 | 907.605
2948723 | 지상 4층 | 지상 4층 | 2948716 | 975 | 0.801835 | 0.019244 | 822.395
3189851 | 지상 4층 | 지상 4층 | 2948716 | 975 | 0.6981 | 0.0167544 | 716
3189794 | 지상 4층 | 지상 4층 | 2948716 | 975 | 0.6981 | 0.0167544 | 716
3189732 | 지상 4층 | 지상 4층 | 2948716 | 975 | 0.6981 | 0.0167544 | 716
2949019 | 지상 4층 | 지상 4층 | 2948716 | 975 | 0.6981 | 0.0167544 | 716
2949008 | 지상 4층 | 지상 4층 | 2948716 | 975 | 0.6981 | 0.0167544 | 716
2948997 | 지상 4층 | 지상 4층 | 2948716 | 975 | 0.6981 | 0.0167544 | 716
2948990 | 지상 4층 | 지상 4층 | 2948716 | 975 | 0.6981 | 0.0167544 | 716
2948979 | 지상 4층 | 지상 4층 | 2948716 | 975 | 0.6981 | 0.0167544 | 716
2948968 | 지상 4층 | 지상 4층 | 2948716 | 975 | 0.6981 | 0.0167544 | 716
2948957 | 지상 4층 | 지상 4층 | 2948716 | 975 | 0.6981 | 0.0167544 | 716
2948913 | 지상 4층 | 지상 4층 | 2948716 | 975 | 0.6981 | 0.0167544 | 716
2948924 | 지상 4층 | 지상 4층 | 2948716 | 975 | 0.62595 | 0.0150228 | 642
2948935 | 지상 4층 | 지상 4층 | 2948716 | 975 | 0.68445 | 0.0164268 | 702
2948946 | 지상 4층 | 지상 4층 | 2948716 | 975 | 0.884915 | 0.021238 | 907.605
2949932 | 지상 4층 | 지상 4층 | 2949931 | 325 | 0.273163 | 0.0065559 | 840.5
2949946 | 지상 4층 | 지상 4층 | 2949931 | 325 | 0.2275 | 0.00546 | 700
2949957 | 지상 4층 | 지상 4층 | 2949931 | 325 | 0.236925 | 0.0056862 | 729
2950311 | 지상 4층 | 지상 4층 | 2949931 | 325 | 0.236925 | 0.0056862 | 729
2949968 | 지상 4층 | 지상 4층 | 2949931 | 325 | 0.236925 | 0.0056862 | 729
2949979 | 지상 4층 | 지상 4층 | 2949931 | 325 | 0.236925 | 0.0056862 | 729
2949990 | 지상 4층 | 지상 4층 | 2949931 | 325 | 0.236925 | 0.0056862 | 729
2950001 | 지상 4층 | 지상 4층 | 2949931 | 325 | 0.236925 | 0.0056862 | 729
2950012 | 지상 4층 | 지상 4층 | 2949931 | 325 | 0.236925 | 0.0056862 | 729
2950023 | 지상 4층 | 지상 4층 | 2949931 | 325 | 0.256425 | 0.0061542 | 789
2950034 | 지상 4층 | 지상 4층 | 2949931 | 325 | 0.325 | 0.0078 | 1000
2950056 | 지상 4층 | 지상 4층 | 2949931 | 325 | 0.2522 | 0.0060528 | 776
2950300 | 지상 4층 | 지상 4층 | 2949931 | 325 | 0.2327 | 0.0055848 | 716
2950045 | 지상 4층 | 지상 4층 | 2949931 | 325 | 0.2327 | 0.0055848 | 716
2950067 | 지상 4층 | 지상 4층 | 2949931 | 325 | 0.2327 | 0.0055848 | 716
2950254 | 지상 4층 | 지상 4층 | 2949931 | 325 | 0.2327 | 0.0055848 | 716
2950243 | 지상 4층 | 지상 4층 | 2949931 | 325 | 0.2327 | 0.0055848 | 716
2950078 | 지상 4층 | 지상 4층 | 2949931 | 325 | 0.2327 | 0.0055848 | 716
2950093 | 지상 4층 | 지상 4층 | 2949931 | 325 | 0.285187 | 0.0068445 | 877.5
2950035 | 지상 4층 | 지상 4층 | 2949931 | 550 | 0.55 | 0.0132 | 1000
2949938 | 지상 4층 | 지상 4층 | 2949931 | 1025 | 0.861513 | 0.0206763 | 840.5
2949948 | 지상 4층 | 지상 4층 | 2949931 | 1025 | 0.7175 | 0.01722 | 700
2949959 | 지상 4층 | 지상 4층 | 2949931 | 1025 | 0.747225 | 0.0179334 | 729
2950313 | 지상 4층 | 지상 4층 | 2949931 | 1025 | 0.747225 | 0.0179334 | 729
2949970 | 지상 4층 | 지상 4층 | 2949931 | 1025 | 0.747225 | 0.0179334 | 729
2949981 | 지상 4층 | 지상 4층 | 2949931 | 1025 | 0.747225 | 0.0179334 | 729
2949992 | 지상 4층 | 지상 4층 | 2949931 | 1025 | 0.747225 | 0.0179334 | 729
2950003 | 지상 4층 | 지상 4층 | 2949931 | 1025 | 0.747225 | 0.0179334 | 729
2950014 | 지상 4층 | 지상 4층 | 2949931 | 1025 | 0.747225 | 0.0179334 | 729
2950025 | 지상 4층 | 지상 4층 | 2949931 | 1025 | 0.808725 | 0.0194094 | 789
2950036 | 지상 4층 | 지상 4층 | 2949931 | 1025 | 1.025 | 0.0246 | 1000
2950058 | 지상 4층 | 지상 4층 | 2949931 | 1025 | 0.7954 | 0.0190896 | 776
2950302 | 지상 4층 | 지상 4층 | 2949931 | 1025 | 0.7339 | 0.0176136 | 716
2950047 | 지상 4층 | 지상 4층 | 2949931 | 1025 | 0.7339 | 0.0176136 | 716
2950069 | 지상 4층 | 지상 4층 | 2949931 | 1025 | 0.7339 | 0.0176136 | 716
2950256 | 지상 4층 | 지상 4층 | 2949931 | 1025 | 0.7339 | 0.0176136 | 716
2950245 | 지상 4층 | 지상 4층 | 2949931 | 1025 | 0.7339 | 0.0176136 | 716
2950080 | 지상 4층 | 지상 4층 | 2949931 | 1025 | 0.7339 | 0.0176136 | 716
2950095 | 지상 4층 | 지상 4층 | 2949931 | 1025 | 0.899437 | 0.0215865 | 877.5
2951076 | 지상 3층 | 지상 3층 | 2951075 | 875 | 0.941514 | 0.0225963 | 1076.02
2952518 | 지상 3층 | 지상 3층 | 2951075 | 875 | 0.813749 | 0.01953 | 929.999
2952698 | 지상 3층 | 지상 3층 | 2951075 | 875 | 0.813749 | 0.01953 | 929.999
2952786 | 지상 3층 | 지상 3층 | 2951075 | 875 | 0.813749 | 0.01953 | 929.999
2952824 | 지상 3층 | 지상 3층 | 2951075 | 875 | 0.813749 | 0.01953 | 929.999
2952862 | 지상 3층 | 지상 3층 | 2951075 | 875 | 0.813749 | 0.01953 | 929.999
2952900 | 지상 3층 | 지상 3층 | 2951075 | 875 | 0.813749 | 0.01953 | 929.999
2952938 | 지상 3층 | 지상 3층 | 2951075 | 875 | 0.813749 | 0.01953 | 929.999
2953115 | 지상 3층 | 지상 3층 | 2951075 | 875 | 0.791874 | 0.019005 | 904.999
2952168 | 지상 3층 | 지상 3층 | 2951075 | 995 | 1.07064 | 0.0256953 | 1076.02
2952520 | 지상 3층 | 지상 3층 | 2951075 | 995 | 0.925349 | 0.0222084 | 929.999
2952700 | 지상 3층 | 지상 3층 | 2951075 | 995 | 0.925349 | 0.0222084 | 929.999
2952788 | 지상 3층 | 지상 3층 | 2951075 | 995 | 0.925349 | 0.0222084 | 929.999
2952826 | 지상 3층 | 지상 3층 | 2951075 | 995 | 0.925349 | 0.0222084 | 929.999
2952864 | 지상 3층 | 지상 3층 | 2951075 | 995 | 0.925349 | 0.0222084 | 929.999
2952902 | 지상 3층 | 지상 3층 | 2951075 | 995 | 0.925349 | 0.0222084 | 929.999
2952940 | 지상 3층 | 지상 3층 | 2951075 | 995 | 0.925349 | 0.0222084 | 929.999
2953117 | 지상 3층 | 지상 3층 | 2951075 | 995 | 0.900474 | 0.0216114 | 904.999
2960447 | 지상 10층 | 지상 10층 | 2960446 | 225 | 0.0401388 | 0.000963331 | 178.395
2960463 | 지상 10층 | 지상 10층 | 2960446 | 225 | 0.372825 | 0.0089478 | 1657
2960474 | 지상 10층 | 지상 10층 | 2960446 | 225 | 0.372825 | 0.0089478 | 1657
2960485 | 지상 10층 | 지상 10층 | 2960446 | 225 | 0.372825 | 0.0089478 | 1657
2960496 | 지상 10층 | 지상 10층 | 2960446 | 225 | 0.372825 | 0.0089478 | 1657
2960507 | 지상 10층 | 지상 10층 | 2960446 | 225 | 0.252 | 0.006048 | 1120
2960518 | 지상 10층 | 지상 10층 | 2960446 | 225 | 0.3393 | 0.0081432 | 1508
2960529 | 지상 10층 | 지상 10층 | 2960446 | 225 | 0.3393 | 0.0081432 | 1508
2960540 | 지상 10층 | 지상 10층 | 2960446 | 225 | 0.3393 | 0.0081432 | 1508
2960551 | 지상 10층 | 지상 10층 | 2960446 | 225 | 0.3393 | 0.0081432 | 1508
2960562 | 지상 10층 | 지상 10층 | 2960446 | 225 | 0.252 | 0.006048 | 1120
2960573 | 지상 10층 | 지상 10층 | 2960446 | 225 | 0.333675 | 0.0080082 | 1483
2960584 | 지상 10층 | 지상 10층 | 2960446 | 225 | 0.333675 | 0.0080082 | 1483
2960595 | 지상 10층 | 지상 10층 | 2960446 | 225 | 0.333675 | 0.0080082 | 1483
2960606 | 지상 10층 | 지상 10층 | 2960446 | 225 | 0.333675 | 0.0080082 | 1483
2960617 | 지상 10층 | 지상 10층 | 2960446 | 225 | 0.252 | 0.006048 | 1120
2960628 | 지상 10층 | 지상 10층 | 2960446 | 225 | 0.334511 | 0.00802826 | 1486.71
2960639 | 지상 10층 | 지상 10층 | 2960446 | 225 | 0.334511 | 0.00802826 | 1486.71
2960650 | 지상 10층 | 지상 10층 | 2960446 | 225 | 0.334511 | 0.00802826 | 1486.71
2960661 | 지상 10층 | 지상 10층 | 2960446 | 225 | 0.334511 | 0.00802826 | 1486.71
2960672 | 지상 10층 | 지상 10층 | 2960446 | 225 | 0.334511 | 0.00802826 | 1486.71
2960683 | 지상 10층 | 지상 10층 | 2960446 | 225 | 0.334511 | 0.00802826 | 1486.71
2960694 | 지상 10층 | 지상 10층 | 2960446 | 225 | 0.334511 | 0.00802826 | 1486.71
2960705 | 지상 10층 | 지상 10층 | 2960446 | 225 | 0.20534 | 0.00492817 | 912.623
2960453 | 지상 10층 | 지상 10층 | 2960446 | 550 | 0.098117 | 0.00235481 | 178.395
2960508 | 지상 10층 | 지상 10층 | 2960446 | 550 | 0.616 | 0.014784 | 1120
2960563 | 지상 10층 | 지상 10층 | 2960446 | 550 | 0.616 | 0.014784 | 1120
2960618 | 지상 10층 | 지상 10층 | 2960446 | 550 | 0.616 | 0.014784 | 1120
2960706 | 지상 10층 | 지상 10층 | 2960446 | 550 | 0.501943 | 0.0120466 | 912.623
2960458 | 지상 10층 | 지상 10층 | 2960446 | 2025 | 0.361249 | 0.00866998 | 178.395
2960465 | 지상 10층 | 지상 10층 | 2960446 | 2025 | 3.35543 | 0.0805302 | 1657
2960476 | 지상 10층 | 지상 10층 | 2960446 | 2025 | 3.35543 | 0.0805302 | 1657
2960487 | 지상 10층 | 지상 10층 | 2960446 | 2025 | 3.35543 | 0.0805302 | 1657
2960498 | 지상 10층 | 지상 10층 | 2960446 | 2025 | 3.35543 | 0.0805302 | 1657
2960509 | 지상 10층 | 지상 10층 | 2960446 | 2025 | 2.268 | 0.054432 | 1120
2960520 | 지상 10층 | 지상 10층 | 2960446 | 2025 | 3.0537 | 0.0732888 | 1508
2960531 | 지상 10층 | 지상 10층 | 2960446 | 2025 | 3.0537 | 0.0732888 | 1508
2960542 | 지상 10층 | 지상 10층 | 2960446 | 2025 | 3.0537 | 0.0732888 | 1508
2960553 | 지상 10층 | 지상 10층 | 2960446 | 2025 | 3.0537 | 0.0732888 | 1508
2960564 | 지상 10층 | 지상 10층 | 2960446 | 2025 | 2.268 | 0.054432 | 1120
2960575 | 지상 10층 | 지상 10층 | 2960446 | 2025 | 3.00308 | 0.0720738 | 1483
2960586 | 지상 10층 | 지상 10층 | 2960446 | 2025 | 3.00308 | 0.0720738 | 1483
2960597 | 지상 10층 | 지상 10층 | 2960446 | 2025 | 3.00308 | 0.0720738 | 1483
2960608 | 지상 10층 | 지상 10층 | 2960446 | 2025 | 3.00308 | 0.0720738 | 1483
2960619 | 지상 10층 | 지상 10층 | 2960446 | 2025 | 2.268 | 0.054432 | 1120
2960630 | 지상 10층 | 지상 10층 | 2960446 | 2025 | 3.0106 | 0.0722543 | 1486.71
2960641 | 지상 10층 | 지상 10층 | 2960446 | 2025 | 3.0106 | 0.0722543 | 1486.71
2960652 | 지상 10층 | 지상 10층 | 2960446 | 2025 | 3.0106 | 0.0722543 | 1486.71
2960663 | 지상 10층 | 지상 10층 | 2960446 | 2025 | 3.0106 | 0.0722543 | 1486.71
2960674 | 지상 10층 | 지상 10층 | 2960446 | 2025 | 3.0106 | 0.0722543 | 1486.71
2960685 | 지상 10층 | 지상 10층 | 2960446 | 2025 | 3.0106 | 0.0722543 | 1486.71
2960696 | 지상 10층 | 지상 10층 | 2960446 | 2025 | 3.0106 | 0.0722543 | 1486.71
2960707 | 지상 10층 | 지상 10층 | 2960446 | 2025 | 1.84806 | 0.0443535 | 912.623
2970486 | 지상 10층 | 지상 10층 | 2970485 | 225 | 0.205384 | 0.00492921 | 912.816
2970502 | 지상 10층 | 지상 10층 | 2970485 | 225 | 0.42975 | 0.010314 | 1910
2970513 | 지상 10층 | 지상 10층 | 2970485 | 225 | 0.423 | 0.010152 | 1880
2970524 | 지상 10층 | 지상 10층 | 2970485 | 225 | 0.423 | 0.010152 | 1880
2970535 | 지상 10층 | 지상 10층 | 2970485 | 225 | 0.423 | 0.010152 | 1880
2970546 | 지상 10층 | 지상 10층 | 2970485 | 225 | 0.423 | 0.010152 | 1880
2970557 | 지상 10층 | 지상 10층 | 2970485 | 225 | 0.42975 | 0.010314 | 1910
2970568 | 지상 10층 | 지상 10층 | 2970485 | 225 | 0.22725 | 0.005454 | 1010
2970579 | 지상 10층 | 지상 10층 | 2970485 | 225 | 0.49275 | 0.011826 | 2190
2970590 | 지상 10층 | 지상 10층 | 2970485 | 225 | 0.22725 | 0.005454 | 1010
2970601 | 지상 10층 | 지상 10층 | 2970485 | 225 | 0.423 | 0.010152 | 1880
2970612 | 지상 10층 | 지상 10층 | 2970485 | 225 | 0.423 | 0.010152 | 1880
2970623 | 지상 10층 | 지상 10층 | 2970485 | 225 | 0.423 | 0.010152 | 1880
2970634 | 지상 10층 | 지상 10층 | 2970485 | 225 | 0.423 | 0.010152 | 1880
2970645 | 지상 10층 | 지상 10층 | 2970485 | 225 | 0.421875 | 0.010125 | 1875
2970656 | 지상 10층 | 지상 10층 | 2970485 | 225 | 0.22725 | 0.005454 | 1010
2970667 | 지상 10층 | 지상 10층 | 2970485 | 225 | 0.435375 | 0.010449 | 1935
2970678 | 지상 10층 | 지상 10층 | 2970485 | 225 | 0.423 | 0.010152 | 1880
2970689 | 지상 10층 | 지상 10층 | 2970485 | 225 | 0.423 | 0.010152 | 1880
2970700 | 지상 10층 | 지상 10층 | 2970485 | 225 | 0.423 | 0.010152 | 1880
2970711 | 지상 10층 | 지상 10층 | 2970485 | 225 | 0.228375 | 0.005481 | 1015
2970722 | 지상 10층 | 지상 10층 | 2970485 | 225 | 0.200909 | 0.00482181 | 892.928
2970492 | 지상 10층 | 지상 10층 | 2970485 | 550 | 0.502049 | 0.0120492 | 912.816
2970569 | 지상 10층 | 지상 10층 | 2970485 | 550 | 0.5555 | 0.013332 | 1010
2970591 | 지상 10층 | 지상 10층 | 2970485 | 550 | 0.5555 | 0.013332 | 1010
2970657 | 지상 10층 | 지상 10층 | 2970485 | 550 | 0.5555 | 0.013332 | 1010
2970723 | 지상 10층 | 지상 10층 | 2970485 | 550 | 0.49111 | 0.0117866 | 892.928
2970497 | 지상 10층 | 지상 10층 | 2970485 | 2025 | 1.84845 | 0.0443629 | 912.816
2970504 | 지상 10층 | 지상 10층 | 2970485 | 2025 | 3.86775 | 0.092826 | 1910
2970515 | 지상 10층 | 지상 10층 | 2970485 | 2025 | 3.807 | 0.091368 | 1880
2970526 | 지상 10층 | 지상 10층 | 2970485 | 2025 | 3.807 | 0.091368 | 1880
2970537 | 지상 10층 | 지상 10층 | 2970485 | 2025 | 3.807 | 0.091368 | 1880
2970548 | 지상 10층 | 지상 10층 | 2970485 | 2025 | 3.807 | 0.091368 | 1880
2970559 | 지상 10층 | 지상 10층 | 2970485 | 2025 | 3.86775 | 0.092826 | 1910
2970570 | 지상 10층 | 지상 10층 | 2970485 | 2025 | 2.04525 | 0.049086 | 1010
2970581 | 지상 10층 | 지상 10층 | 2970485 | 2025 | 4.43475 | 0.106434 | 2190
2970592 | 지상 10층 | 지상 10층 | 2970485 | 2025 | 2.04525 | 0.049086 | 1010
2970603 | 지상 10층 | 지상 10층 | 2970485 | 2025 | 3.807 | 0.091368 | 1880
2970614 | 지상 10층 | 지상 10층 | 2970485 | 2025 | 3.807 | 0.091368 | 1880
2970625 | 지상 10층 | 지상 10층 | 2970485 | 2025 | 3.807 | 0.091368 | 1880
2970636 | 지상 10층 | 지상 10층 | 2970485 | 2025 | 3.807 | 0.091368 | 1880
2970647 | 지상 10층 | 지상 10층 | 2970485 | 2025 | 3.79688 | 0.091125 | 1875
2970658 | 지상 10층 | 지상 10층 | 2970485 | 2025 | 2.04525 | 0.049086 | 1010
2970669 | 지상 10층 | 지상 10층 | 2970485 | 2025 | 3.91838 | 0.094041 | 1935
2970680 | 지상 10층 | 지상 10층 | 2970485 | 2025 | 3.807 | 0.091368 | 1880
2970691 | 지상 10층 | 지상 10층 | 2970485 | 2025 | 3.807 | 0.091368 | 1880
2970702 | 지상 10층 | 지상 10층 | 2970485 | 2025 | 3.807 | 0.091368 | 1880
2970713 | 지상 10층 | 지상 10층 | 2970485 | 2025 | 2.05538 | 0.049329 | 1015
2970724 | 지상 10층 | 지상 10층 | 2970485 | 2025 | 1.80818 | 0.0433963 | 892.928
2971240 | 지상 5층 | 지상 5층 | 2971239 | 225 | 0.375903 | 0.00902167 | 1670.68
2973907 | 지상 5층 | 지상 5층 | 2971239 | 225 | 0.340578 | 0.00817387 | 1513.68
2973813 | 지상 5층 | 지상 5층 | 2971239 | 225 | 0.340578 | 0.00817387 | 1513.68
2973739 | 지상 5층 | 지상 5층 | 2971239 | 225 | 0.340578 | 0.00817387 | 1513.68
2973689 | 지상 5층 | 지상 5층 | 2971239 | 225 | 0.340578 | 0.00817387 | 1513.68
2973565 | 지상 5층 | 지상 5층 | 2971239 | 225 | 0.225 | 0.0054 | 1000
2973517 | 지상 5층 | 지상 5층 | 2971239 | 225 | 0.3402 | 0.0081648 | 1512
2973437 | 지상 5층 | 지상 5층 | 2971239 | 225 | 0.3402 | 0.0081648 | 1512
2973321 | 지상 5층 | 지상 5층 | 2971239 | 225 | 0.3402 | 0.0081648 | 1512
2973219 | 지상 5층 | 지상 5층 | 2971239 | 225 | 0.3402 | 0.0081648 | 1512
2973071 | 지상 5층 | 지상 5층 | 2971239 | 225 | 0.225 | 0.0054 | 1000
2972994 | 지상 5층 | 지상 5층 | 2971239 | 225 | 0.328937 | 0.0078945 | 1461.94
2972882 | 지상 5층 | 지상 5층 | 2971239 | 225 | 0.328937 | 0.0078945 | 1461.94
2972768 | 지상 5층 | 지상 5층 | 2971239 | 225 | 0.328937 | 0.0078945 | 1461.94
2972662 | 지상 5층 | 지상 5층 | 2971239 | 225 | 0.328937 | 0.0078945 | 1461.94
2972568 | 지상 5층 | 지상 5층 | 2971239 | 225 | 0.328937 | 0.0078945 | 1461.94
2972473 | 지상 5층 | 지상 5층 | 2971239 | 225 | 0.328937 | 0.0078945 | 1461.94
2972376 | 지상 5층 | 지상 5층 | 2971239 | 225 | 0.328937 | 0.0078945 | 1461.94
2971953 | 지상 5층 | 지상 5층 | 2971239 | 225 | 0.230625 | 0.005535 | 1025
2973566 | 지상 5층 | 지상 5층 | 2971239 | 550 | 0.55 | 0.0132 | 1000
2973072 | 지상 5층 | 지상 5층 | 2971239 | 550 | 0.55 | 0.0132 | 1000
2971954 | 지상 5층 | 지상 5층 | 2971239 | 550 | 0.56375 | 0.01353 | 1025
2971745 | 지상 5층 | 지상 5층 | 2971239 | 1025 | 1.71245 | 0.0410987 | 1670.68
2973909 | 지상 5층 | 지상 5층 | 2971239 | 1025 | 1.55152 | 0.0372365 | 1513.68
2973815 | 지상 5층 | 지상 5층 | 2971239 | 1025 | 1.55152 | 0.0372365 | 1513.68
2973741 | 지상 5층 | 지상 5층 | 2971239 | 1025 | 1.55152 | 0.0372365 | 1513.68
2973691 | 지상 5층 | 지상 5층 | 2971239 | 1025 | 1.55152 | 0.0372365 | 1513.68
2973567 | 지상 5층 | 지상 5층 | 2971239 | 1025 | 1.025 | 0.0246 | 1000
2973519 | 지상 5층 | 지상 5층 | 2971239 | 1025 | 1.5498 | 0.0371952 | 1512
2973439 | 지상 5층 | 지상 5층 | 2971239 | 1025 | 1.5498 | 0.0371952 | 1512
2973323 | 지상 5층 | 지상 5층 | 2971239 | 1025 | 1.5498 | 0.0371952 | 1512
2973221 | 지상 5층 | 지상 5층 | 2971239 | 1025 | 1.5498 | 0.0371952 | 1512
2973073 | 지상 5층 | 지상 5층 | 2971239 | 1025 | 1.025 | 0.0246 | 1000
2972996 | 지상 5층 | 지상 5층 | 2971239 | 1025 | 1.49849 | 0.0359638 | 1461.94
2972884 | 지상 5층 | 지상 5층 | 2971239 | 1025 | 1.49849 | 0.0359638 | 1461.94
2972770 | 지상 5층 | 지상 5층 | 2971239 | 1025 | 1.49849 | 0.0359638 | 1461.94
2972664 | 지상 5층 | 지상 5층 | 2971239 | 1025 | 1.49849 | 0.0359638 | 1461.94
2972570 | 지상 5층 | 지상 5층 | 2971239 | 1025 | 1.49849 | 0.0359638 | 1461.94
2972475 | 지상 5층 | 지상 5층 | 2971239 | 1025 | 1.49849 | 0.0359638 | 1461.94
2972378 | 지상 5층 | 지상 5층 | 2971239 | 1025 | 1.49849 | 0.0359638 | 1461.94
2971955 | 지상 5층 | 지상 5층 | 2971239 | 1025 | 1.05062 | 0.025215 | 1025
2975043 | 지상 6층 | 지상 6층 | 2975042 | 225 | 0.367514 | 0.00882033 | 1633.39
2975246 | 지상 6층 | 지상 6층 | 2975042 | 225 | 0.3393 | 0.0081432 | 1508
2975235 | 지상 6층 | 지상 6층 | 2975042 | 225 | 0.3393 | 0.0081432 | 1508
2975224 | 지상 6층 | 지상 6층 | 2975042 | 225 | 0.3393 | 0.0081432 | 1508
2975213 | 지상 6층 | 지상 6층 | 2975042 | 225 | 0.3528 | 0.0084672 | 1568
2975202 | 지상 6층 | 지상 6층 | 2975042 | 225 | 0.225 | 0.0054 | 1000
2975191 | 지상 6층 | 지상 6층 | 2975042 | 225 | 0.34695 | 0.0083268 | 1542
2975180 | 지상 6층 | 지상 6층 | 2975042 | 225 | 0.33345 | 0.0080028 | 1482
2975169 | 지상 6층 | 지상 6층 | 2975042 | 225 | 0.33345 | 0.0080028 | 1482
2975158 | 지상 6층 | 지상 6층 | 2975042 | 225 | 0.34695 | 0.0083268 | 1542
2975147 | 지상 6층 | 지상 6층 | 2975042 | 225 | 0.225 | 0.0054 | 1000
2975136 | 지상 6층 | 지상 6층 | 2975042 | 225 | 0.34695 | 0.0083268 | 1542
2975125 | 지상 6층 | 지상 6층 | 2975042 | 225 | 0.33345 | 0.0080028 | 1482
2975114 | 지상 6층 | 지상 6층 | 2975042 | 225 | 0.33345 | 0.0080028 | 1482
2975103 | 지상 6층 | 지상 6층 | 2975042 | 225 | 0.33345 | 0.0080028 | 1482
2975092 | 지상 6층 | 지상 6층 | 2975042 | 225 | 0.33345 | 0.0080028 | 1482
2975081 | 지상 6층 | 지상 6층 | 2975042 | 225 | 0.33345 | 0.0080028 | 1482
2975070 | 지상 6층 | 지상 6층 | 2975042 | 225 | 0.31365 | 0.0075276 | 1394
2975059 | 지상 6층 | 지상 6층 | 2975042 | 225 | 0.205336 | 0.00492807 | 912.605
2975203 | 지상 6층 | 지상 6층 | 2975042 | 550 | 0.55 | 0.0132 | 1000
2975148 | 지상 6층 | 지상 6층 | 2975042 | 550 | 0.55 | 0.0132 | 1000
2975060 | 지상 6층 | 지상 6층 | 2975042 | 550 | 0.501933 | 0.0120464 | 912.605
2975054 | 지상 6층 | 지상 6층 | 2975042 | 1025 | 1.67423 | 0.0401815 | 1633.39
2975248 | 지상 6층 | 지상 6층 | 2975042 | 1025 | 1.5457 | 0.0370968 | 1508
2975237 | 지상 6층 | 지상 6층 | 2975042 | 1025 | 1.5457 | 0.0370968 | 1508
2975226 | 지상 6층 | 지상 6층 | 2975042 | 1025 | 1.5457 | 0.0370968 | 1508
2975215 | 지상 6층 | 지상 6층 | 2975042 | 1025 | 1.6072 | 0.0385728 | 1568
2975204 | 지상 6층 | 지상 6층 | 2975042 | 1025 | 1.025 | 0.0246 | 1000
2975193 | 지상 6층 | 지상 6층 | 2975042 | 1025 | 1.58055 | 0.0379332 | 1542
2975182 | 지상 6층 | 지상 6층 | 2975042 | 1025 | 1.51905 | 0.0364572 | 1482
2975171 | 지상 6층 | 지상 6층 | 2975042 | 1025 | 1.51905 | 0.0364572 | 1482
2975160 | 지상 6층 | 지상 6층 | 2975042 | 1025 | 1.58055 | 0.0379332 | 1542
2975149 | 지상 6층 | 지상 6층 | 2975042 | 1025 | 1.025 | 0.0246 | 1000
2975138 | 지상 6층 | 지상 6층 | 2975042 | 1025 | 1.58055 | 0.0379332 | 1542
2975127 | 지상 6층 | 지상 6층 | 2975042 | 1025 | 1.51905 | 0.0364572 | 1482
2975116 | 지상 6층 | 지상 6층 | 2975042 | 1025 | 1.51905 | 0.0364572 | 1482
2975105 | 지상 6층 | 지상 6층 | 2975042 | 1025 | 1.51905 | 0.0364572 | 1482
2975094 | 지상 6층 | 지상 6층 | 2975042 | 1025 | 1.51905 | 0.0364572 | 1482
2975083 | 지상 6층 | 지상 6층 | 2975042 | 1025 | 1.51905 | 0.0364572 | 1482
2975072 | 지상 6층 | 지상 6층 | 2975042 | 1025 | 1.42885 | 0.0342924 | 1394
2975061 | 지상 6층 | 지상 6층 | 2975042 | 1025 | 0.935421 | 0.0224501 | 912.605
2975403 | 지상 7층 | 지상 7층 | 2975402 | 225 | 0.326564 | 0.00783753 | 1451.39
2975606 | 지상 7층 | 지상 7층 | 2975402 | 225 | 0.3393 | 0.0081432 | 1508
2975595 | 지상 7층 | 지상 7층 | 2975402 | 225 | 0.3393 | 0.0081432 | 1508
2975584 | 지상 7층 | 지상 7층 | 2975402 | 225 | 0.3393 | 0.0081432 | 1508
2975573 | 지상 7층 | 지상 7층 | 2975402 | 225 | 0.3528 | 0.0084672 | 1568
2975562 | 지상 7층 | 지상 7층 | 2975402 | 225 | 0.225 | 0.0054 | 1000
2975551 | 지상 7층 | 지상 7층 | 2975402 | 225 | 0.34695 | 0.0083268 | 1542
2975540 | 지상 7층 | 지상 7층 | 2975402 | 225 | 0.33345 | 0.0080028 | 1482
2975529 | 지상 7층 | 지상 7층 | 2975402 | 225 | 0.33345 | 0.0080028 | 1482
2975518 | 지상 7층 | 지상 7층 | 2975402 | 225 | 0.34695 | 0.0083268 | 1542
2975507 | 지상 7층 | 지상 7층 | 2975402 | 225 | 0.225 | 0.0054 | 1000
2975496 | 지상 7층 | 지상 7층 | 2975402 | 225 | 0.34695 | 0.0083268 | 1542
2975485 | 지상 7층 | 지상 7층 | 2975402 | 225 | 0.33345 | 0.0080028 | 1482
2975474 | 지상 7층 | 지상 7층 | 2975402 | 225 | 0.33345 | 0.0080028 | 1482
2975463 | 지상 7층 | 지상 7층 | 2975402 | 225 | 0.33345 | 0.0080028 | 1482
2975452 | 지상 7층 | 지상 7층 | 2975402 | 225 | 0.33345 | 0.0080028 | 1482
2975441 | 지상 7층 | 지상 7층 | 2975402 | 225 | 0.33345 | 0.0080028 | 1482
2975430 | 지상 7층 | 지상 7층 | 2975402 | 225 | 0.31365 | 0.0075276 | 1394
2975419 | 지상 7층 | 지상 7층 | 2975402 | 225 | 0.205336 | 0.00492807 | 912.605
2975563 | 지상 7층 | 지상 7층 | 2975402 | 550 | 0.55 | 0.0132 | 1000
2975508 | 지상 7층 | 지상 7층 | 2975402 | 550 | 0.55 | 0.0132 | 1000
2975420 | 지상 7층 | 지상 7층 | 2975402 | 550 | 0.501933 | 0.0120464 | 912.605
2975414 | 지상 7층 | 지상 7층 | 2975402 | 1025 | 1.48768 | 0.0357043 | 1451.39
2975608 | 지상 7층 | 지상 7층 | 2975402 | 1025 | 1.5457 | 0.0370968 | 1508
2975597 | 지상 7층 | 지상 7층 | 2975402 | 1025 | 1.5457 | 0.0370968 | 1508
2975586 | 지상 7층 | 지상 7층 | 2975402 | 1025 | 1.5457 | 0.0370968 | 1508
2975575 | 지상 7층 | 지상 7층 | 2975402 | 1025 | 1.6072 | 0.0385728 | 1568
2975564 | 지상 7층 | 지상 7층 | 2975402 | 1025 | 1.025 | 0.0246 | 1000
2975553 | 지상 7층 | 지상 7층 | 2975402 | 1025 | 1.58055 | 0.0379332 | 1542
2975542 | 지상 7층 | 지상 7층 | 2975402 | 1025 | 1.51905 | 0.0364572 | 1482
2975531 | 지상 7층 | 지상 7층 | 2975402 | 1025 | 1.51905 | 0.0364572 | 1482
2975520 | 지상 7층 | 지상 7층 | 2975402 | 1025 | 1.58055 | 0.0379332 | 1542
2975509 | 지상 7층 | 지상 7층 | 2975402 | 1025 | 1.025 | 0.0246 | 1000
2975498 | 지상 7층 | 지상 7층 | 2975402 | 1025 | 1.58055 | 0.0379332 | 1542
2975487 | 지상 7층 | 지상 7층 | 2975402 | 1025 | 1.51905 | 0.0364572 | 1482
2975476 | 지상 7층 | 지상 7층 | 2975402 | 1025 | 1.51905 | 0.0364572 | 1482
2975465 | 지상 7층 | 지상 7층 | 2975402 | 1025 | 1.51905 | 0.0364572 | 1482
2975454 | 지상 7층 | 지상 7층 | 2975402 | 1025 | 1.51905 | 0.0364572 | 1482
2975443 | 지상 7층 | 지상 7층 | 2975402 | 1025 | 1.51905 | 0.0364572 | 1482
2975432 | 지상 7층 | 지상 7층 | 2975402 | 1025 | 1.42885 | 0.0342924 | 1394
2975421 | 지상 7층 | 지상 7층 | 2975402 | 1025 | 0.935421 | 0.0224501 | 912.605
2975763 | 지상 8층 | 지상 8층 | 2975762 | 225 | 0.367514 | 0.00882033 | 1633.39
2975966 | 지상 8층 | 지상 8층 | 2975762 | 225 | 0.3393 | 0.0081432 | 1508
2975955 | 지상 8층 | 지상 8층 | 2975762 | 225 | 0.3393 | 0.0081432 | 1508
2975944 | 지상 8층 | 지상 8층 | 2975762 | 225 | 0.3393 | 0.0081432 | 1508
2975933 | 지상 8층 | 지상 8층 | 2975762 | 225 | 0.3528 | 0.0084672 | 1568
2975922 | 지상 8층 | 지상 8층 | 2975762 | 225 | 0.225 | 0.0054 | 1000
2975911 | 지상 8층 | 지상 8층 | 2975762 | 225 | 0.34695 | 0.0083268 | 1542
2975900 | 지상 8층 | 지상 8층 | 2975762 | 225 | 0.33345 | 0.0080028 | 1482
2975889 | 지상 8층 | 지상 8층 | 2975762 | 225 | 0.33345 | 0.0080028 | 1482
2975878 | 지상 8층 | 지상 8층 | 2975762 | 225 | 0.34695 | 0.0083268 | 1542
2975867 | 지상 8층 | 지상 8층 | 2975762 | 225 | 0.225 | 0.0054 | 1000
2975856 | 지상 8층 | 지상 8층 | 2975762 | 225 | 0.34695 | 0.0083268 | 1542
2975845 | 지상 8층 | 지상 8층 | 2975762 | 225 | 0.33345 | 0.0080028 | 1482
2975834 | 지상 8층 | 지상 8층 | 2975762 | 225 | 0.33345 | 0.0080028 | 1482
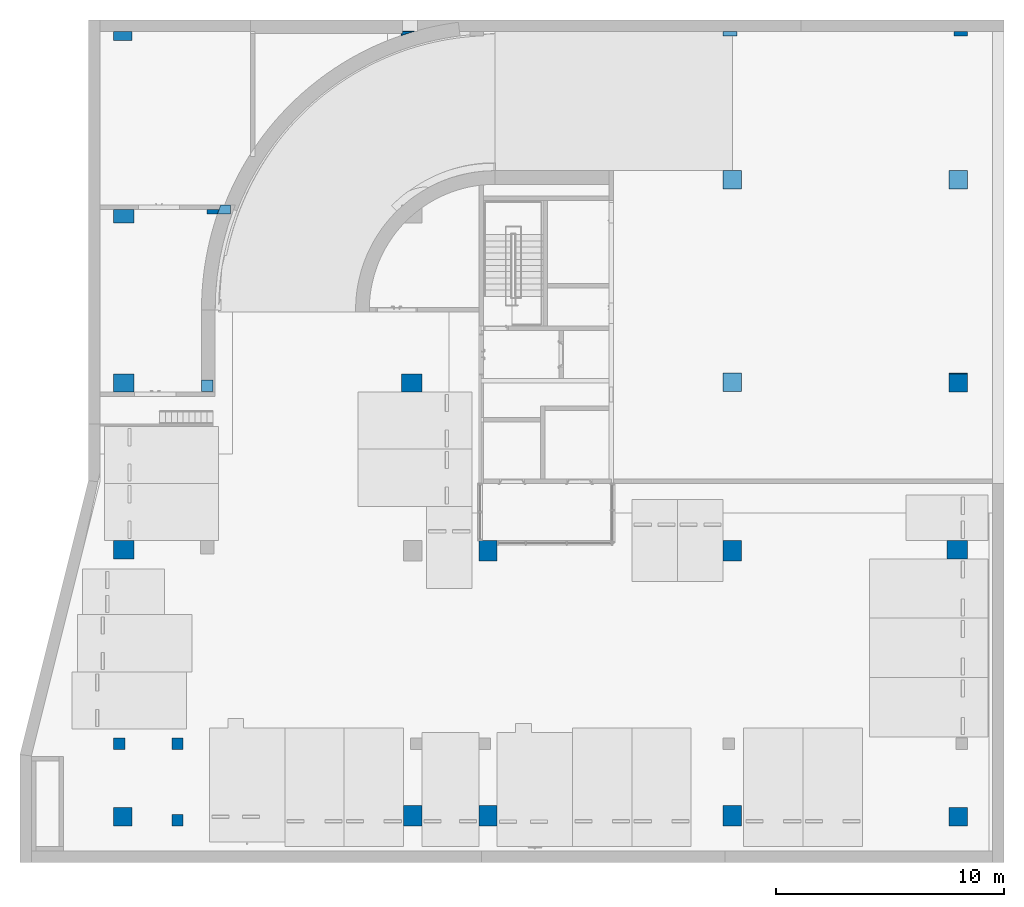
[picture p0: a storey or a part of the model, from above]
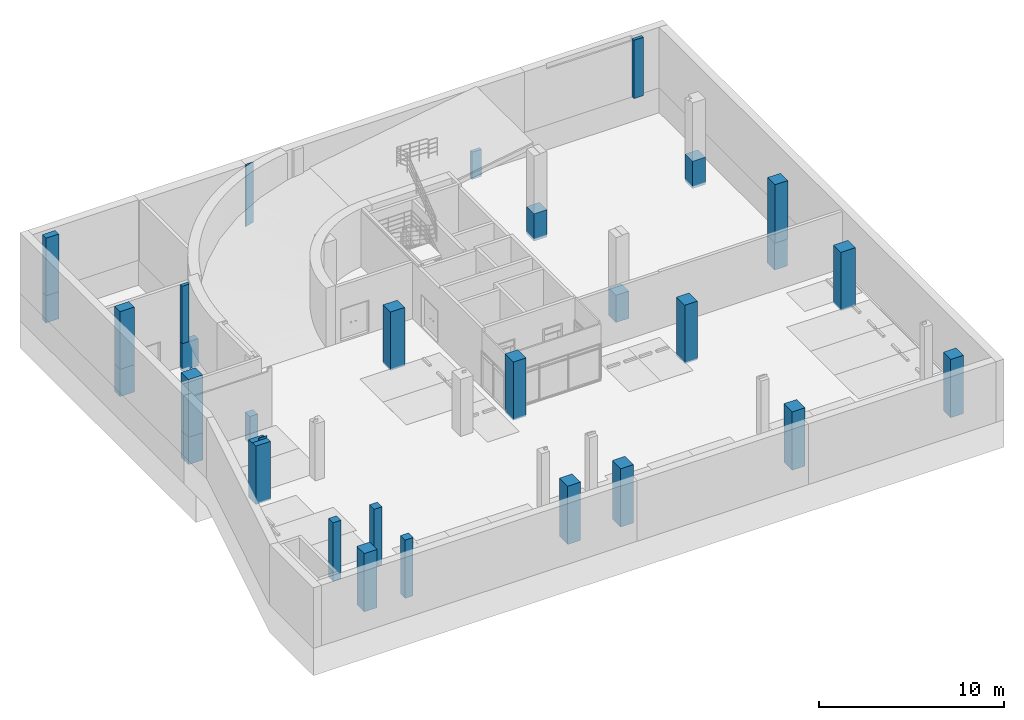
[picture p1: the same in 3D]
Properties of the parts of a building model (IFC2X3), part 30 of 39

# IfcPlate: CW300-THK24.Low-e coating glass:CW300-THK24.Low-e coating glass (2337)
Name (CW300-THK24.Low-e coating glass:CW300-THK24.Low-e coating glass:...) | In | 레벨 | 호스트 ID | 높이 (mm) | 면적 (m2) | 체적 (m3) = NetVolume (m3) | 폭 (mm)
2975823 | 지상 8층 | 지상 8층 | 2975762 | 225 | 0.33345 | 0.0080028 | 1482
2975812 | 지상 8층 | 지상 8층 | 2975762 | 225 | 0.33345 | 0.0080028 | 1482
2975801 | 지상 8층 | 지상 8층 | 2975762 | 225 | 0.33345 | 0.0080028 | 1482
2975790 | 지상 8층 | 지상 8층 | 2975762 | 225 | 0.31365 | 0.0075276 | 1394
2975779 | 지상 8층 | 지상 8층 | 2975762 | 225 | 0.205336 | 0.00492807 | 912.605
2975923 | 지상 8층 | 지상 8층 | 2975762 | 550 | 0.55 | 0.0132 | 1000
2975868 | 지상 8층 | 지상 8층 | 2975762 | 550 | 0.55 | 0.0132 | 1000
2975780 | 지상 8층 | 지상 8층 | 2975762 | 550 | 0.501933 | 0.0120464 | 912.605
2975774 | 지상 8층 | 지상 8층 | 2975762 | 1025 | 1.67423 | 0.0401815 | 1633.39
2975968 | 지상 8층 | 지상 8층 | 2975762 | 1025 | 1.5457 | 0.0370968 | 1508
2975957 | 지상 8층 | 지상 8층 | 2975762 | 1025 | 1.5457 | 0.0370968 | 1508
2975946 | 지상 8층 | 지상 8층 | 2975762 | 1025 | 1.5457 | 0.0370968 | 1508
2975935 | 지상 8층 | 지상 8층 | 2975762 | 1025 | 1.6072 | 0.0385728 | 1568
2975924 | 지상 8층 | 지상 8층 | 2975762 | 1025 | 1.025 | 0.0246 | 1000
2975913 | 지상 8층 | 지상 8층 | 2975762 | 1025 | 1.58055 | 0.0379332 | 1542
2975902 | 지상 8층 | 지상 8층 | 2975762 | 1025 | 1.51905 | 0.0364572 | 1482
2975891 | 지상 8층 | 지상 8층 | 2975762 | 1025 | 1.51905 | 0.0364572 | 1482
2975880 | 지상 8층 | 지상 8층 | 2975762 | 1025 | 1.58055 | 0.0379332 | 1542
2975869 | 지상 8층 | 지상 8층 | 2975762 | 1025 | 1.025 | 0.0246 | 1000
2975858 | 지상 8층 | 지상 8층 | 2975762 | 1025 | 1.58055 | 0.0379332 | 1542
2975847 | 지상 8층 | 지상 8층 | 2975762 | 1025 | 1.51905 | 0.0364572 | 1482
2975836 | 지상 8층 | 지상 8층 | 2975762 | 1025 | 1.51905 | 0.0364572 | 1482
2975825 | 지상 8층 | 지상 8층 | 2975762 | 1025 | 1.51905 | 0.0364572 | 1482
2975814 | 지상 8층 | 지상 8층 | 2975762 | 1025 | 1.51905 | 0.0364572 | 1482
2975803 | 지상 8층 | 지상 8층 | 2975762 | 1025 | 1.51905 | 0.0364572 | 1482
2975792 | 지상 8층 | 지상 8층 | 2975762 | 1025 | 1.42885 | 0.0342924 | 1394
2975781 | 지상 8층 | 지상 8층 | 2975762 | 1025 | 0.935421 | 0.0224501 | 912.605
2976123 | 지상 9층 | 지상 9층 | 2976122 | 225 | 0.326564 | 0.00783753 | 1451.39
2976326 | 지상 9층 | 지상 9층 | 2976122 | 225 | 0.3393 | 0.0081432 | 1508
2976315 | 지상 9층 | 지상 9층 | 2976122 | 225 | 0.3393 | 0.0081432 | 1508
2976304 | 지상 9층 | 지상 9층 | 2976122 | 225 | 0.3393 | 0.0081432 | 1508
2976293 | 지상 9층 | 지상 9층 | 2976122 | 225 | 0.3528 | 0.0084672 | 1568
2976282 | 지상 9층 | 지상 9층 | 2976122 | 225 | 0.225 | 0.0054 | 1000
2976271 | 지상 9층 | 지상 9층 | 2976122 | 225 | 0.34695 | 0.0083268 | 1542
2976260 | 지상 9층 | 지상 9층 | 2976122 | 225 | 0.33345 | 0.0080028 | 1482
2976249 | 지상 9층 | 지상 9층 | 2976122 | 225 | 0.33345 | 0.0080028 | 1482
2976238 | 지상 9층 | 지상 9층 | 2976122 | 225 | 0.34695 | 0.0083268 | 1542
2976227 | 지상 9층 | 지상 9층 | 2976122 | 225 | 0.225 | 0.0054 | 1000
2976216 | 지상 9층 | 지상 9층 | 2976122 | 225 | 0.34695 | 0.0083268 | 1542
2976205 | 지상 9층 | 지상 9층 | 2976122 | 225 | 0.33345 | 0.0080028 | 1482
2976194 | 지상 9층 | 지상 9층 | 2976122 | 225 | 0.33345 | 0.0080028 | 1482
2976183 | 지상 9층 | 지상 9층 | 2976122 | 225 | 0.33345 | 0.0080028 | 1482
2976172 | 지상 9층 | 지상 9층 | 2976122 | 225 | 0.33345 | 0.0080028 | 1482
2976161 | 지상 9층 | 지상 9층 | 2976122 | 225 | 0.33345 | 0.0080028 | 1482
2976150 | 지상 9층 | 지상 9층 | 2976122 | 225 | 0.31365 | 0.0075276 | 1394
2976139 | 지상 9층 | 지상 9층 | 2976122 | 225 | 0.205336 | 0.00492807 | 912.605
2976283 | 지상 9층 | 지상 9층 | 2976122 | 550 | 0.55 | 0.0132 | 1000
2976228 | 지상 9층 | 지상 9층 | 2976122 | 550 | 0.55 | 0.0132 | 1000
2976140 | 지상 9층 | 지상 9층 | 2976122 | 550 | 0.501933 | 0.0120464 | 912.605
2976134 | 지상 9층 | 지상 9층 | 2976122 | 1525 | 2.21338 | 0.053121 | 1451.39
2976328 | 지상 9층 | 지상 9층 | 2976122 | 1525 | 2.2997 | 0.0551928 | 1508
2976317 | 지상 9층 | 지상 9층 | 2976122 | 1525 | 2.2997 | 0.0551928 | 1508
2976306 | 지상 9층 | 지상 9층 | 2976122 | 1525 | 2.2997 | 0.0551928 | 1508
2976295 | 지상 9층 | 지상 9층 | 2976122 | 1525 | 2.3912 | 0.0573888 | 1568
2976284 | 지상 9층 | 지상 9층 | 2976122 | 1525 | 1.525 | 0.0366 | 1000
2976273 | 지상 9층 | 지상 9층 | 2976122 | 1525 | 2.35155 | 0.0564372 | 1542
2976262 | 지상 9층 | 지상 9층 | 2976122 | 1525 | 2.26005 | 0.0542412 | 1482
2976251 | 지상 9층 | 지상 9층 | 2976122 | 1525 | 2.26005 | 0.0542412 | 1482
2976240 | 지상 9층 | 지상 9층 | 2976122 | 1525 | 2.35155 | 0.0564372 | 1542
2976229 | 지상 9층 | 지상 9층 | 2976122 | 1525 | 1.525 | 0.0366 | 1000
2976218 | 지상 9층 | 지상 9층 | 2976122 | 1525 | 2.35155 | 0.0564372 | 1542
2976207 | 지상 9층 | 지상 9층 | 2976122 | 1525 | 2.26005 | 0.0542412 | 1482
2976196 | 지상 9층 | 지상 9층 | 2976122 | 1525 | 2.26005 | 0.0542412 | 1482
2976185 | 지상 9층 | 지상 9층 | 2976122 | 1525 | 2.26005 | 0.0542412 | 1482
2976174 | 지상 9층 | 지상 9층 | 2976122 | 1525 | 2.26005 | 0.0542412 | 1482
2976163 | 지상 9층 | 지상 9층 | 2976122 | 1525 | 2.26005 | 0.0542412 | 1482
2976152 | 지상 9층 | 지상 9층 | 2976122 | 1525 | 2.12585 | 0.0510204 | 1394
2976141 | 지상 9층 | 지상 9층 | 2976122 | 1525 | 1.39172 | 0.0334014 | 912.605
2976483 | 지상 10층 | 지상 10층 | 2976482 | 225 | 0.371564 | 0.00891753 | 1651.39
2976686 | 지상 10층 | 지상 10층 | 2976482 | 225 | 0.3393 | 0.0081432 | 1508
2976675 | 지상 10층 | 지상 10층 | 2976482 | 225 | 0.3393 | 0.0081432 | 1508
2976664 | 지상 10층 | 지상 10층 | 2976482 | 225 | 0.3393 | 0.0081432 | 1508
2976653 | 지상 10층 | 지상 10층 | 2976482 | 225 | 0.3528 | 0.0084672 | 1568
2976642 | 지상 10층 | 지상 10층 | 2976482 | 225 | 0.225 | 0.0054 | 1000
2976631 | 지상 10층 | 지상 10층 | 2976482 | 225 | 0.34695 | 0.0083268 | 1542
2976620 | 지상 10층 | 지상 10층 | 2976482 | 225 | 0.33345 | 0.0080028 | 1482
2976609 | 지상 10층 | 지상 10층 | 2976482 | 225 | 0.33345 | 0.0080028 | 1482
2976598 | 지상 10층 | 지상 10층 | 2976482 | 225 | 0.34695 | 0.0083268 | 1542
2976587 | 지상 10층 | 지상 10층 | 2976482 | 225 | 0.225 | 0.0054 | 1000
2976576 | 지상 10층 | 지상 10층 | 2976482 | 225 | 0.34695 | 0.0083268 | 1542
2976565 | 지상 10층 | 지상 10층 | 2976482 | 225 | 0.33345 | 0.0080028 | 1482
2976554 | 지상 10층 | 지상 10층 | 2976482 | 225 | 0.33345 | 0.0080028 | 1482
2976543 | 지상 10층 | 지상 10층 | 2976482 | 225 | 0.33345 | 0.0080028 | 1482
2976532 | 지상 10층 | 지상 10층 | 2976482 | 225 | 0.33345 | 0.0080028 | 1482
2976521 | 지상 10층 | 지상 10층 | 2976482 | 225 | 0.33345 | 0.0080028 | 1482
2976510 | 지상 10층 | 지상 10층 | 2976482 | 225 | 0.31365 | 0.0075276 | 1394
2976499 | 지상 10층 | 지상 10층 | 2976482 | 225 | 0.205336 | 0.00492807 | 912.605
2976643 | 지상 10층 | 지상 10층 | 2976482 | 550 | 0.55 | 0.0132 | 1000
2976588 | 지상 10층 | 지상 10층 | 2976482 | 550 | 0.55 | 0.0132 | 1000
2976500 | 지상 10층 | 지상 10층 | 2976482 | 550 | 0.501933 | 0.0120464 | 912.605
2976494 | 지상 10층 | 지상 10층 | 2976482 | 2025 | 3.34407 | 0.0802578 | 1651.39
2976688 | 지상 10층 | 지상 10층 | 2976482 | 2025 | 3.0537 | 0.0732888 | 1508
2976677 | 지상 10층 | 지상 10층 | 2976482 | 2025 | 3.0537 | 0.0732888 | 1508
2976666 | 지상 10층 | 지상 10층 | 2976482 | 2025 | 3.0537 | 0.0732888 | 1508
2976655 | 지상 10층 | 지상 10층 | 2976482 | 2025 | 3.1752 | 0.0762048 | 1568
2976644 | 지상 10층 | 지상 10층 | 2976482 | 2025 | 2.025 | 0.0486 | 1000
2976633 | 지상 10층 | 지상 10층 | 2976482 | 2025 | 3.12255 | 0.0749412 | 1542
2976622 | 지상 10층 | 지상 10층 | 2976482 | 2025 | 3.00105 | 0.0720252 | 1482
2976611 | 지상 10층 | 지상 10층 | 2976482 | 2025 | 3.00105 | 0.0720252 | 1482
2976600 | 지상 10층 | 지상 10층 | 2976482 | 2025 | 3.12255 | 0.0749412 | 1542
2976589 | 지상 10층 | 지상 10층 | 2976482 | 2025 | 2.025 | 0.0486 | 1000
2976578 | 지상 10층 | 지상 10층 | 2976482 | 2025 | 3.12255 | 0.0749412 | 1542
2976567 | 지상 10층 | 지상 10층 | 2976482 | 2025 | 3.00105 | 0.0720252 | 1482
2976556 | 지상 10층 | 지상 10층 | 2976482 | 2025 | 3.00105 | 0.0720252 | 1482
2976545 | 지상 10층 | 지상 10층 | 2976482 | 2025 | 3.00105 | 0.0720252 | 1482
2976534 | 지상 10층 | 지상 10층 | 2976482 | 2025 | 3.00105 | 0.0720252 | 1482
2976523 | 지상 10층 | 지상 10층 | 2976482 | 2025 | 3.00105 | 0.0720252 | 1482
2976512 | 지상 10층 | 지상 10층 | 2976482 | 2025 | 2.82285 | 0.0677484 | 1394
2976501 | 지상 10층 | 지상 10층 | 2976482 | 2025 | 1.84803 | 0.0443526 | 912.605
3050432 | 지하2층 | 지하2층 | 3050431 | 2025 | 2.37542 | 0.05701 | 1173.05
3051795 | 지하2층 | 지하2층 | 3050431 | 2025 | 2.38333 | 0.0572 | 1176.95
3051980 | 지하2층 | 지하2층 | 3050431 | 215 | 0.252205 | 0.00605291 | 1173.05
3051981 | 지하2층 | 지하2층 | 3050431 | 215 | 0.253045 | 0.00607309 | 1176.95
3050664 | 지하2층 | 지하2층 | 3050663 | 2025 | 2.37938 | 0.057105 | 1175
3052533 | 지하2층 | 지하2층 | 3050663 | 2025 | 3.90825 | 0.093798 | 1930
3052280 | 지하2층 | 지하2층 | 3050663 | 215 | 0.252625 | 0.006063 | 1175
3052448 | 지하2층 | 지하2층 | 3050663 | 215 | 0.37625 | 0.00903 | 1750
3052534 | 지하2층 | 지하2층 | 3050663 | 215 | 0.41495 | 0.0099588 | 1930
3050963 | 지하2층 | 지하2층 | 3050962 | 2025 | 2.21066 | 0.0530559 | 1091.68
3053488 | 지하2층 | 지하2층 | 3050962 | 2025 | 2.75059 | 0.0660141 | 1358.32
3053267 | 지하2층 | 지하2층 | 3050962 | 215 | 0.234712 | 0.00563309 | 1091.68
3053489 | 지하2층 | 지하2층 | 3050962 | 215 | 0.292038 | 0.00700891 | 1358.32
3054004 | 지하1층 | 지하1층 | 3054003 | 2025 | 2.37542 | 0.05701 | 1173.05
3054022 | 지하1층 | 지하1층 | 3054003 | 2025 | 2.37542 | 0.05701 | 1173.05
3054027 | 지하1층 | 지하1층 | 3054003 | 425 | 0.498544 | 0.0119651 | 1173.05
3054028 | 지하1층 | 지하1층 | 3054003 | 425 | 0.498544 | 0.0119651 | 1173.05
3054010 | 지하1층 | 지하1층 | 3054009 | 2025 | 2.37938 | 0.057105 | 1175
3054048 | 지하1층 | 지하1층 | 3054009 | 2025 | 3.89812 | 0.093555 | 1925
3054035 | 지하1층 | 지하1층 | 3054009 | 425 | 0.499375 | 0.011985 | 1175
3054041 | 지하1층 | 지하1층 | 3054009 | 425 | 0.74375 | 0.01785 | 1750
3054049 | 지하1층 | 지하1층 | 3054009 | 425 | 0.818125 | 0.019635 | 1925
3054016 | 지하1층 | 지하1층 | 3054015 | 2025 | 2.21066 | 0.0530559 | 1091.68
3054061 | 지하1층 | 지하1층 | 3054015 | 2025 | 2.74267 | 0.0658241 | 1354.41
3054056 | 지하1층 | 지하1층 | 3054015 | 425 | 0.463966 | 0.0111352 | 1091.68
3054062 | 지하1층 | 지하1층 | 3054015 | 425 | 0.575622 | 0.0138149 | 1354.41
3118406 | 지상 1층 | 지상 1층 | 3118405 | 2025 | 0.556672 | 0.0133601 | 274.9
3118412 | 지상 1층 | 지상 1층 | 3118405 | 2025 | 0.648238 | 0.0155577 | 320.118
3118422 | 지상 1층 | 지상 1층 | 3118405 | 1345 | 3.28855 | 0.0789252 | 2445.02
3181692 | 지상 2층 | 지상 2층 | 3181685 | 975 | 0.219383 | 0.0052652 | 225.009
3181698 | 지상 2층 | 지상 2층 | 3181685 | 895 | 0.201383 | 0.00483319 | 225.009
3181717 | 지상 3층 | 지상 3층 | 3181710 | 975 | 0.170625 | 0.004095 | 175
3181723 | 지상 3층 | 지상 3층 | 3181710 | 895 | 0.156625 | 0.003759 | 175
3181738 | 지상 4층 | 지상 4층 | 3181731 | 1025 | 0.179375 | 0.004305 | 175
3181744 | 지상 4층 | 지상 4층 | 3181731 | 895 | 0.156625 | 0.003759 | 175
3181759 | 지상 5층 | 지상 5층 | 3181752 | 1025 | 0.230634 | 0.00553521 | 225.009
3181765 | 지상 5층 | 지상 5층 | 3181752 | 895 | 0.201383 | 0.00483319 | 225.009
3181780 | 지상 6층 | 지상 6층 | 3181773 | 1025 | 0.230634 | 0.00553521 | 225.009
3181786 | 지상 6층 | 지상 6층 | 3181773 | 895 | 0.201383 | 0.00483319 | 225.009
3181801 | 지상 7층 | 지상 7층 | 3181794 | 1025 | 0.230634 | 0.00553521 | 225.009
3181807 | 지상 7층 | 지상 7층 | 3181794 | 895 | 0.201383 | 0.00483319 | 225.009
3181822 | 지상 8층 | 지상 8층 | 3181815 | 1025 | 0.230634 | 0.00553521 | 225.009
3181828 | 지상 8층 | 지상 8층 | 3181815 | 895 | 0.201383 | 0.00483319 | 225.009
3181843 | 지상 9층 | 지상 9층 | 3181836 | 1025 | 0.230634 | 0.00553521 | 225.009
3181849 | 지상 9층 | 지상 9층 | 3181836 | 895 | 0.201383 | 0.00483319 | 225.009
3181864 | 지상 10층 | 지상 10층 | 3181857 | 1025 | 0.497134 | 0.0119312 | 485.009
3181870 | 지상 10층 | 지상 10층 | 3181857 | 895 | 0.434083 | 0.010418 | 485.009
5355391 | 지상 4층 | 지상 4층 | 5355390 | 2025 | 0.864417 | 0.020746 | 426.873
5355410 | 지상 4층 | 지상 4층 | 5355390 | 2025 | 0.856833 | 0.020564 | 423.127
5355397 | 지상 4층 | 지상 4층 | 5355390 | 445 | 0.189958 | 0.004559 | 426.873
5355403 | 지상 4층 | 지상 4층 | 5355390 | 445 | 0.64525 | 0.015486 | 1450
5355411 | 지상 4층 | 지상 4층 | 5355390 | 445 | 0.188292 | 0.004519 | 423.127
5355418 | 지상 4층 | 지상 4층 | 5355417 | 2075 | 4.69988 | 0.112797 | 2265
5355424 | 지상 4층 | 지상 4층 | 5355417 | 2075 | 5.46762 | 0.131223 | 2635
5355434 | 지상 4층 | 지상 4층 | 5355417 | 445 | 1.00793 | 0.0241902 | 2265
5355435 | 지상 4층 | 지상 4층 | 5355417 | 445 | 0.6675 | 0.01602 | 1500
5355436 | 지상 4층 | 지상 4층 | 5355417 | 445 | 1.17258 | 0.0281418 | 2635
5355472 | 지상 4층 | 지상 4층 | 5355471 | 2025 | 0.76315 | 0.0183156 | 376.864
5355491 | 지상 4층 | 지상 4층 | 5355471 | 2025 | 0.856921 | 0.0205661 | 423.171
5355478 | 지상 4층 | 지상 4층 | 5355471 | 445 | 0.167704 | 0.00402491 | 376.864
5355484 | 지상 4층 | 지상 4층 | 5355471 | 445 | 0.6675 | 0.01602 | 1500
5355492 | 지상 4층 | 지상 4층 | 5355471 | 445 | 0.188311 | 0.00451946 | 423.171
5355499 | 지상 4층 | 지상 4층 | 5355498 | 2025 | 3.61463 | 0.086751 | 1785
5355510 | 지상 4층 | 지상 4층 | 5355498 | 2025 | 3.66525 | 0.087966 | 1810
5355526 | 지상 4층 | 지상 4층 | 5355498 | 2025 | 4.9005 | 0.117612 | 2420
5355534 | 지상 4층 | 지상 4층 | 5355498 | 2025 | 4.22212 | 0.101331 | 2085
5355505 | 지상 4층 | 지상 4층 | 5355498 | 445 | 0.794325 | 0.0190638 | 1785
5355511 | 지상 4층 | 지상 4층 | 5355498 | 445 | 0.80545 | 0.0193308 | 1810
5355519 | 지상 4층 | 지상 4층 | 5355498 | 445 | 0.6675 | 0.01602 | 1500
5355527 | 지상 4층 | 지상 4층 | 5355498 | 445 | 1.0769 | 0.0258456 | 2420
5355535 | 지상 4층 | 지상 4층 | 5355498 | 445 | 0.927825 | 0.0222678 | 2085
5389071 | 지상 4층 | 지상 4층 | 5389070 | 2025 | 4.22212 | 0.101331 | 2085
5389089 | 지상 4층 | 지상 4층 | 5389070 | 445 | 0.927825 | 0.0222678 | 2085
5389521 | 지상 4층 | 지상 4층 | 5389520 | 2075 | 1.0375 | 0.0249 | 500
5389540 | 지상 4층 | 지상 4층 | 5389520 | 2075 | 1.01682 | 0.0244037 | 490.035
5389532 | 지상 4층 | 지상 4층 | 5389520 | 445 | 0.2225 | 0.00534 | 500
5389533 | 지상 4층 | 지상 4층 | 5389520 | 445 | 0.6675 | 0.01602 | 1500
5389541 | 지상 4층 | 지상 4층 | 5389520 | 445 | 0.218066 | 0.00523357 | 490.035
5393178 | 지상 9층 | 지상 9층 | 5393177 | 2025 | 4.35375 | 0.10449 | 2150
5393196 | 지상 9층 | 지상 9층 | 5393177 | 845 | 1.81675 | 0.043602 | 2150
5393184 | 지상 9층 | 지상 9층 | 5393183 | 2075 | 0.944053 | 0.0226573 | 454.965
5393214 | 지상 9층 | 지상 9층 | 5393183 | 2075 | 1.1102 | 0.0266447 | 535.034
5393206 | 지상 9층 | 지상 9층 | 5393183 | 845 | 0.384446 | 0.00922669 | 454.965
5393207 | 지상 9층 | 지상 9층 | 5393183 | 845 | 1.2675 | 0.03042 | 1500
5393215 | 지상 9층 | 지상 9층 | 5393183 | 845 | 0.452104 | 0.0108505 | 535.034
5393190 | 지상 9층 | 지상 9층 | 5393189 | 2075 | 1.57698 | 0.0378476 | 759.991
7696730 | 지상 9층 | 지상 9층 | 5393189 | 2075 | 0.581018 | 0.0139444 | 280.009
5393222 | 지상 9층 | 지상 9층 | 5393189 | 845 | 0.642193 | 0.0154126 | 759.991
5393228 | 지상 9층 | 지상 9층 | 5393189 | 845 | 1.26328 | 0.0303186 | 1495
7696731 | 지상 9층 | 지상 9층 | 5393189 | 845 | 0.236607 | 0.00567858 | 280.009
5396620 | 지상 5층 | 지상 5층 | 5396619 | 2075 | 0.885689 | 0.0212565 | 426.838
5396639 | 지상 5층 | 지상 5층 | 5396619 | 2075 | 0.878061 | 0.0210735 | 423.162
5396626 | 지상 5층 | 지상 5층 | 5396619 | 445 | 0.189943 | 0.00455863 | 426.838
5396632 | 지상 5층 | 지상 5층 | 5396619 | 445 | 0.64525 | 0.015486 | 1450
5396640 | 지상 5층 | 지상 5층 | 5396619 | 445 | 0.188307 | 0.00451937 | 423.162
5396649 | 지상 6층 | 지상 6층 | 5396648 | 2075 | 0.885689 | 0.0212565 | 426.838
5396668 | 지상 6층 | 지상 6층 | 5396648 | 2075 | 0.878079 | 0.0210739 | 423.171
5396655 | 지상 6층 | 지상 6층 | 5396648 | 445 | 0.189943 | 0.00455863 | 426.838
5396661 | 지상 6층 | 지상 6층 | 5396648 | 445 | 0.64525 | 0.015486 | 1450
5396669 | 지상 6층 | 지상 6층 | 5396648 | 445 | 0.188311 | 0.00451946 | 423.171
5396678 | 지상 7층 | 지상 7층 | 5396677 | 2075 | 0.885689 | 0.0212565 | 426.838
5396697 | 지상 7층 | 지상 7층 | 5396677 | 2075 | 0.878061 | 0.0210735 | 423.162
5396684 | 지상 7층 | 지상 7층 | 5396677 | 445 | 0.189943 | 0.00455863 | 426.838
5396690 | 지상 7층 | 지상 7층 | 5396677 | 445 | 0.64525 | 0.015486 | 1450
5396698 | 지상 7층 | 지상 7층 | 5396677 | 445 | 0.188307 | 0.00451937 | 423.162
5396707 | 지상 8층 | 지상 8층 | 5396706 | 2075 | 0.881841 | 0.0211642 | 424.983
5396726 | 지상 8층 | 지상 8층 | 5396706 | 2075 | 0.881927 | 0.0211663 | 425.025
5396713 | 지상 8층 | 지상 8층 | 5396706 | 445 | 0.189118 | 0.00453882 | 424.983
5396719 | 지상 8층 | 지상 8층 | 5396706 | 445 | 0.64525 | 0.015486 | 1450
5396727 | 지상 8층 | 지상 8층 | 5396706 | 445 | 0.189136 | 0.00453927 | 425.025
5397132 | 지상 5층 | 지상 5층 | 5397131 | 2075 | 4.69995 | 0.112799 | 2265.03
5397138 | 지상 5층 | 지상 5층 | 5397131 | 2075 | 5.26005 | 0.126241 | 2534.97
5397148 | 지상 5층 | 지상 5층 | 5397131 | 445 | 1.00794 | 0.0241906 | 2265.03
5397149 | 지상 5층 | 지상 5층 | 5397131 | 445 | 0.6675 | 0.01602 | 1500
5397150 | 지상 5층 | 지상 5층 | 5397131 | 445 | 1.12806 | 0.0270734 | 2534.97
5397159 | 지상 5층 | 지상 5층 | 5397158 | 2075 | 4.69988 | 0.112797 | 2265
5397165 | 지상 5층 | 지상 5층 | 5397158 | 2075 | 5.46762 | 0.131223 | 2635
5397175 | 지상 5층 | 지상 5층 | 5397158 | 445 | 1.00793 | 0.0241902 | 2265
5397176 | 지상 5층 | 지상 5층 | 5397158 | 445 | 0.6675 | 0.01602 | 1500
5397177 | 지상 5층 | 지상 5층 | 5397158 | 445 | 1.17258 | 0.0281418 | 2635
5397188 | 지상 6층 | 지상 6층 | 5397187 | 2075 | 4.69995 | 0.112799 | 2265.03
5397194 | 지상 6층 | 지상 6층 | 5397187 | 2075 | 5.26005 | 0.126241 | 2534.97
5397204 | 지상 6층 | 지상 6층 | 5397187 | 445 | 1.00794 | 0.0241906 | 2265.03
5397205 | 지상 6층 | 지상 6층 | 5397187 | 445 | 0.6675 | 0.01602 | 1500
5397206 | 지상 6층 | 지상 6층 | 5397187 | 445 | 1.12806 | 0.0270734 | 2534.97
5397215 | 지상 6층 | 지상 6층 | 5397214 | 2075 | 4.69988 | 0.112797 | 2265
5397221 | 지상 6층 | 지상 6층 | 5397214 | 2075 | 5.46762 | 0.131223 | 2635
5397231 | 지상 6층 | 지상 6층 | 5397214 | 445 | 1.00793 | 0.0241902 | 2265
5397232 | 지상 6층 | 지상 6층 | 5397214 | 445 | 0.6675 | 0.01602 | 1500
5397233 | 지상 6층 | 지상 6층 | 5397214 | 445 | 1.17258 | 0.0281418 | 2635
5397244 | 지상 7층 | 지상 7층 | 5397243 | 2075 | 4.69988 | 0.112797 | 2265
5397250 | 지상 7층 | 지상 7층 | 5397243 | 2075 | 5.24968 | 0.125992 | 2529.97
5397260 | 지상 7층 | 지상 7층 | 5397243 | 445 | 1.00793 | 0.0241902 | 2265
5397261 | 지상 7층 | 지상 7층 | 5397243 | 445 | 0.6675 | 0.01602 | 1500
5397262 | 지상 7층 | 지상 7층 | 5397243 | 445 | 1.12583 | 0.02702 | 2529.97
5397271 | 지상 7층 | 지상 7층 | 5397270 | 2075 | 4.69988 | 0.112797 | 2265
5397277 | 지상 7층 | 지상 7층 | 5397270 | 2075 | 5.46762 | 0.131223 | 2635
5397287 | 지상 7층 | 지상 7층 | 5397270 | 445 | 1.00793 | 0.0241902 | 2265
5397288 | 지상 7층 | 지상 7층 | 5397270 | 445 | 0.6675 | 0.01602 | 1500
5397289 | 지상 7층 | 지상 7층 | 5397270 | 445 | 1.17258 | 0.0281418 | 2635
5397300 | 지상 8층 | 지상 8층 | 5397299 | 2075 | 4.69988 | 0.112797 | 2265
5397306 | 지상 8층 | 지상 8층 | 5397299 | 2075 | 5.26005 | 0.126241 | 2534.97
5397316 | 지상 8층 | 지상 8층 | 5397299 | 445 | 1.00793 | 0.0241902 | 2265
5397317 | 지상 8층 | 지상 8층 | 5397299 | 445 | 0.6675 | 0.01602 | 1500
5397318 | 지상 8층 | 지상 8층 | 5397299 | 445 | 1.12806 | 0.0270734 | 2534.97
5397327 | 지상 8층 | 지상 8층 | 5397326 | 2075 | 4.90738 | 0.117777 | 2365
5397333 | 지상 8층 | 지상 8층 | 5397326 | 2075 | 5.6752 | 0.136205 | 2735.03
5397343 | 지상 8층 | 지상 8층 | 5397326 | 445 | 1.05242 | 0.0252582 | 2365
5397344 | 지상 8층 | 지상 8층 | 5397326 | 445 | 0.6675 | 0.01602 | 1500
5397345 | 지상 8층 | 지상 8층 | 5397326 | 445 | 1.21709 | 0.0292102 | 2735.03
5398148 | 지상 5층 | 지상 5층 | 5398141 | 445 | 0.167697 | 0.00402472 | 376.847
5398154 | 지상 5층 | 지상 5층 | 5398141 | 445 | 0.6675 | 0.01602 | 1500
5398162 | 지상 5층 | 지상 5층 | 5398141 | 445 | 0.188311 | 0.00451946 | 423.171
5398177 | 지상 6층 | 지상 6층 | 5398170 | 445 | 0.167689 | 0.00402454 | 376.829
5398183 | 지상 6층 | 지상 6층 | 5398170 | 445 | 0.6675 | 0.01602 | 1500
5398191 | 지상 6층 | 지상 6층 | 5398170 | 445 | 0.188311 | 0.00451946 | 423.171
5398206 | 지상 7층 | 지상 7층 | 5398199 | 445 | 0.166875 | 0.004005 | 375
5398212 | 지상 7층 | 지상 7층 | 5398199 | 445 | 0.6675 | 0.01602 | 1500
5398220 | 지상 7층 | 지상 7층 | 5398199 | 445 | 0.208325 | 0.00499979 | 468.145
5398235 | 지상 8층 | 지상 8층 | 5398228 | 445 | 0.167697 | 0.00402472 | 376.847
5398241 | 지상 8층 | 지상 8층 | 5398228 | 445 | 0.6675 | 0.01602 | 1500
5398249 | 지상 8층 | 지상 8층 | 5398228 | 445 | 0.188311 | 0.00451946 | 423.171
5398673 | 지상 5층 | 지상 5층 | 5398672 | 2075 | 3.70391 | 0.0888939 | 1785.02
5398684 | 지상 5층 | 지상 5층 | 5398672 | 2075 | 3.75575 | 0.090138 | 1810
5398700 | 지상 5층 | 지상 5층 | 5398672 | 2075 | 5.0215 | 0.120516 | 2420
5398708 | 지상 5층 | 지상 5층 | 5398672 | 2075 | 4.32637 | 0.103833 | 2085
5398679 | 지상 5층 | 지상 5층 | 5398672 | 445 | 0.794333 | 0.019064 | 1785.02
5398685 | 지상 5층 | 지상 5층 | 5398672 | 445 | 0.80545 | 0.0193308 | 1810
5398693 | 지상 5층 | 지상 5층 | 5398672 | 445 | 0.6675 | 0.01602 | 1500
5398701 | 지상 5층 | 지상 5층 | 5398672 | 445 | 1.0769 | 0.0258456 | 2420
5398709 | 지상 5층 | 지상 5층 | 5398672 | 445 | 0.927825 | 0.0222678 | 2085
5398718 | 지상 6층 | 지상 6층 | 5398717 | 2075 | 3.70388 | 0.088893 | 1785
5398729 | 지상 6층 | 지상 6층 | 5398717 | 2075 | 3.75575 | 0.090138 | 1810
5398745 | 지상 6층 | 지상 6층 | 5398717 | 2075 | 5.0215 | 0.120516 | 2420
5398753 | 지상 6층 | 지상 6층 | 5398717 | 2075 | 4.32633 | 0.103832 | 2084.98
5398724 | 지상 6층 | 지상 6층 | 5398717 | 445 | 0.794325 | 0.0190638 | 1785
5398730 | 지상 6층 | 지상 6층 | 5398717 | 445 | 0.80545 | 0.0193308 | 1810
5398738 | 지상 6층 | 지상 6층 | 5398717 | 445 | 0.6675 | 0.01602 | 1500
5398746 | 지상 6층 | 지상 6층 | 5398717 | 445 | 1.0769 | 0.0258456 | 2420
5398754 | 지상 6층 | 지상 6층 | 5398717 | 445 | 0.927816 | 0.0222676 | 2084.98
5398763 | 지상 7층 | 지상 7층 | 5398762 | 2075 | 3.70388 | 0.088893 | 1785
5398774 | 지상 7층 | 지상 7층 | 5398762 | 2075 | 3.75575 | 0.090138 | 1810
5398790 | 지상 7층 | 지상 7층 | 5398762 | 2075 | 5.0215 | 0.120516 | 2420
5398798 | 지상 7층 | 지상 7층 | 5398762 | 2075 | 4.32637 | 0.103833 | 2085
5398769 | 지상 7층 | 지상 7층 | 5398762 | 445 | 0.794325 | 0.0190638 | 1785
5398775 | 지상 7층 | 지상 7층 | 5398762 | 445 | 0.80545 | 0.0193308 | 1810
5398783 | 지상 7층 | 지상 7층 | 5398762 | 445 | 0.6675 | 0.01602 | 1500
5398791 | 지상 7층 | 지상 7층 | 5398762 | 445 | 1.0769 | 0.0258456 | 2420
5398799 | 지상 7층 | 지상 7층 | 5398762 | 445 | 0.927825 | 0.0222678 | 2085
5398808 | 지상 8층 | 지상 8층 | 5398807 | 2075 | 3.91138 | 0.093873 | 1885
5398819 | 지상 8층 | 지상 8층 | 5398807 | 2075 | 3.75575 | 0.090138 | 1810
5398835 | 지상 8층 | 지상 8층 | 5398807 | 2075 | 5.0215 | 0.120516 | 2420
5398843 | 지상 8층 | 지상 8층 | 5398807 | 2075 | 4.32637 | 0.103833 | 2085
5398814 | 지상 8층 | 지상 8층 | 5398807 | 445 | 0.838825 | 0.0201318 | 1885
5398820 | 지상 8층 | 지상 8층 | 5398807 | 445 | 0.80545 | 0.0193308 | 1810
5398828 | 지상 8층 | 지상 8층 | 5398807 | 445 | 0.6675 | 0.01602 | 1500
5398836 | 지상 8층 | 지상 8층 | 5398807 | 445 | 1.0769 | 0.0258456 | 2420
5398844 | 지상 8층 | 지상 8층 | 5398807 | 445 | 0.927825 | 0.0222678 | 2085
5403429 | 지상 5층 | 지상 5층 | 5403428 | 2025 | 4.14112 | 0.099387 | 2045
5403435 | 지상 5층 | 지상 5층 | 5403428 | 445 | 0.910025 | 0.0218406 | 2045
5403440 | 지상 5층 | 지상 5층 | 5403439 | 2075 | 0.935878 | 0.0224611 | 451.025
5403459 | 지상 5층 | 지상 5층 | 5403439 | 2075 | 1.12045 | 0.0268907 | 539.975
5403451 | 지상 5층 | 지상 5층 | 5403439 | 445 | 0.200706 | 0.00481695 | 451.025
5403452 | 지상 5층 | 지상 5층 | 5403439 | 445 | 0.6675 | 0.01602 | 1500
5403460 | 지상 5층 | 지상 5층 | 5403439 | 445 | 0.240289 | 0.00576693 | 539.975
5403467 | 지상 6층 | 지상 6층 | 5403466 | 2025 | 4.14112 | 0.099387 | 2045
5403473 | 지상 6층 | 지상 6층 | 5403466 | 445 | 0.910025 | 0.0218406 | 2045
5403478 | 지상 6층 | 지상 6층 | 5403477 | 2075 | 0.933678 | 0.0224083 | 449.965
5403497 | 지상 6층 | 지상 6층 | 5403477 | 2075 | 0.923447 | 0.0221627 | 445.035
5403489 | 지상 6층 | 지상 6층 | 5403477 | 445 | 0.200234 | 0.00480563 | 449.965
5403490 | 지상 6층 | 지상 6층 | 5403477 | 445 | 0.6675 | 0.01602 | 1500
5403498 | 지상 6층 | 지상 6층 | 5403477 | 445 | 0.198041 | 0.00475297 | 445.035
5403505 | 지상 7층 | 지상 7층 | 5403504 | 2025 | 4.15122 | 0.0996292 | 2049.98
5403511 | 지상 7층 | 지상 7층 | 5403504 | 445 | 0.912243 | 0.0218938 | 2049.98
5403516 | 지상 7층 | 지상 7층 | 5403515 | 2075 | 0.944053 | 0.0226573 | 454.965
5403535 | 지상 7층 | 지상 7층 | 5403515 | 2075 | 0.923448 | 0.0221627 | 445.035
5403527 | 지상 7층 | 지상 7층 | 5403515 | 445 | 0.202459 | 0.00485903 | 454.965
5403528 | 지상 7층 | 지상 7층 | 5403515 | 445 | 0.6675 | 0.01602 | 1500
5403536 | 지상 7층 | 지상 7층 | 5403515 | 445 | 0.198041 | 0.00475297 | 445.035
5403543 | 지상 8층 | 지상 8층 | 5403542 | 2025 | 4.34366 | 0.104248 | 2145.02
5403549 | 지상 8층 | 지상 8층 | 5403542 | 445 | 0.954533 | 0.0229088 | 2145.02
5403554 | 지상 8층 | 지상 8층 | 5403553 | 2075 | 0.923303 | 0.0221593 | 444.965
5403573 | 지상 8층 | 지상 8층 | 5403553 | 2075 | 0.923448 | 0.0221627 | 445.035
5403565 | 지상 8층 | 지상 8층 | 5403553 | 445 | 0.19801 | 0.00475223 | 444.965
5403566 | 지상 8층 | 지상 8층 | 5403553 | 445 | 0.6675 | 0.01602 | 1500
5403574 | 지상 8층 | 지상 8층 | 5403553 | 445 | 0.198041 | 0.00475297 | 445.035
5403581 | 지상 4층 | 지상 4층 | 5403580 | 2075 | 1.48362 | 0.035607 | 715
7697122 | 지상 4층 | 지상 4층 | 5403580 | 2075 | 0.581018 | 0.0139444 | 280.009
5403587 | 지상 4층 | 지상 4층 | 5403580 | 445 | 0.318175 | 0.0076362 | 715
5403593 | 지상 4층 | 지상 4층 | 5403580 | 445 | 0.665275 | 0.0159666 | 1495
7697123 | 지상 4층 | 지상 4층 | 5403580 | 445 | 0.124604 | 0.00299049 | 280.009
5403602 | 지상 5층 | 지상 5층 | 5403601 | 2075 | 1.58736 | 0.0380966 | 764.991
7697028 | 지상 5층 | 지상 5층 | 5403601 | 2075 | 0.581018 | 0.0139444 | 280.009
5403608 | 지상 5층 | 지상 5층 | 5403601 | 445 | 0.340421 | 0.00817011 | 764.991
5403614 | 지상 5층 | 지상 5층 | 5403601 | 445 | 0.665275 | 0.0159666 | 1495
7697029 | 지상 5층 | 지상 5층 | 5403601 | 445 | 0.124604 | 0.00299049 | 280.009
5403621 | 지상 6층 | 지상 6층 | 5403620 | 2075 | 1.57698 | 0.0378476 | 759.991
7696936 | 지상 6층 | 지상 6층 | 5403620 | 2075 | 0.581018 | 0.0139444 | 280.009
5403627 | 지상 6층 | 지상 6층 | 5403620 | 445 | 0.338196 | 0.00811671 | 759.991
5403633 | 지상 6층 | 지상 6층 | 5403620 | 445 | 0.665275 | 0.0159666 | 1495
7696937 | 지상 6층 | 지상 6층 | 5403620 | 445 | 0.124604 | 0.00299049 | 280.009
5403640 | 지상 7층 | 지상 7층 | 5403639 | 2075 | 1.57698 | 0.0378476 | 759.991
7696888 | 지상 7층 | 지상 7층 | 5403639 | 2075 | 0.581018 | 0.0139444 | 280.009
5403646 | 지상 7층 | 지상 7층 | 5403639 | 445 | 0.338196 | 0.00811671 | 759.991
5403652 | 지상 7층 | 지상 7층 | 5403639 | 445 | 0.665275 | 0.0159666 | 1495
7696889 | 지상 7층 | 지상 7층 | 5403639 | 445 | 0.124604 | 0.00299049 | 280.009
5403659 | 지상 8층 | 지상 8층 | 5403658 | 2075 | 1.57698 | 0.0378476 | 759.991
7696798 | 지상 8층 | 지상 8층 | 5403658 | 2075 | 0.581018 | 0.0139444 | 280.009
5403665 | 지상 8층 | 지상 8층 | 5403658 | 445 | 0.338196 | 0.00811671 | 759.991
5403671 | 지상 8층 | 지상 8층 | 5403658 | 445 | 0.665275 | 0.0159666 | 1495
7696799 | 지상 8층 | 지상 8층 | 5403658 | 445 | 0.124604 | 0.00299049 | 280.009
5403678 | 지상 10층 | 지상 10층 | 5403677 | 2025 | 4.35375 | 0.10449 | 2150
5403684 | 지상 10층 | 지상 10층 | 5403677 | 1345 | 2.89175 | 0.069402 | 2150
5403691 | 지상 10층 | 지상 10층 | 5403690 | 2075 | 0.944125 | 0.022659 | 455
5403710 | 지상 10층 | 지상 10층 | 5403690 | 2075 | 0.933678 | 0.0224083 | 449.965
5403702 | 지상 10층 | 지상 10층 | 5403690 | 1345 | 0.611975 | 0.0146874 | 455
5403703 | 지상 10층 | 지상 10층 | 5403690 | 1345 | 2.0175 | 0.04842 | 1500
5403711 | 지상 10층 | 지상 10층 | 5403690 | 1345 | 0.605203 | 0.0145249 | 449.965
5403727 | 지상 10층 | 지상 10층 | 5403726 | 2075 | 1.58737 | 0.038097 | 765
7696640 | 지상 10층 | 지상 10층 | 5403726 | 2075 | 0.581018 | 0.0139444 | 280.009
5403733 | 지상 10층 | 지상 10층 | 5403726 | 1345 | 1.02892 | 0.0246942 | 765
5403739 | 지상 10층 | 지상 10층 | 5403726 | 1345 | 2.01077 | 0.0482586 | 1495
7696641 | 지상 10층 | 지상 10층 | 5403726 | 1345 | 0.376612 | 0.00903868 | 280.009
5405306 | 지상 3층 | 지상 3층 | 5405305 | 2025 | 4.5867 | 0.110081 | 2265.03
5405312 | 지상 3층 | 지상 3층 | 5405305 | 2025 | 5.13338 | 0.123201 | 2535
5405322 | 지상 3층 | 지상 3층 | 5405305 | 445 | 1.00794 | 0.0241906 | 2265.03
5405323 | 지상 3층 | 지상 3층 | 5405305 | 445 | 0.6675 | 0.01602 | 1500
5405324 | 지상 3층 | 지상 3층 | 5405305 | 445 | 1.12808 | 0.0270738 | 2535
5405787 | 지상 3층 | 지상 3층 | 5405786 | 2025 | 4.2525 | 0.10206 | 2100
5405793 | 지상 3층 | 지상 3층 | 5405786 | 445 | 0.9345 | 0.022428 | 2100
5405798 | 지상 3층 | 지상 3층 | 5405797 | 2025 | 0.921304 | 0.0221113 | 454.965
5405817 | 지상 3층 | 지상 3층 | 5405797 | 2025 | 1.20495 | 0.0289187 | 595.035
5405809 | 지상 3층 | 지상 3층 | 5405797 | 445 | 0.202459 | 0.00485903 | 454.965
5405810 | 지상 3층 | 지상 3층 | 5405797 | 445 | 0.6675 | 0.01602 | 1500
5405818 | 지상 3층 | 지상 3층 | 5405797 | 445 | 0.264791 | 0.00635497 | 595.035
5818109 | 지상 9층 | 지상 9층 | 5818108 | 225 | 0.205384 | 0.00492921 | 912.816
5818122 | 지상 9층 | 지상 9층 | 5818108 | 225 | 0.42975 | 0.010314 | 1910
5818133 | 지상 9층 | 지상 9층 | 5818108 | 225 | 0.423 | 0.010152 | 1880
5818144 | 지상 9층 | 지상 9층 | 5818108 | 225 | 0.423 | 0.010152 | 1880
5818155 | 지상 9층 | 지상 9층 | 5818108 | 225 | 0.423 | 0.010152 | 1880
5818166 | 지상 9층 | 지상 9층 | 5818108 | 225 | 0.423 | 0.010152 | 1880
5818177 | 지상 9층 | 지상 9층 | 5818108 | 225 | 0.42975 | 0.010314 | 1910
5818188 | 지상 9층 | 지상 9층 | 5818108 | 225 | 0.22725 | 0.005454 | 1010
5818199 | 지상 9층 | 지상 9층 | 5818108 | 225 | 0.49275 | 0.011826 | 2190
5818210 | 지상 9층 | 지상 9층 | 5818108 | 225 | 0.22725 | 0.005454 | 1010
5818221 | 지상 9층 | 지상 9층 | 5818108 | 225 | 0.423 | 0.010152 | 1880
5818232 | 지상 9층 | 지상 9층 | 5818108 | 225 | 0.423 | 0.010152 | 1880
5818243 | 지상 9층 | 지상 9층 | 5818108 | 225 | 0.423 | 0.010152 | 1880
5818254 | 지상 9층 | 지상 9층 | 5818108 | 225 | 0.423 | 0.010152 | 1880
5818265 | 지상 9층 | 지상 9층 | 5818108 | 225 | 0.421875 | 0.010125 | 1875
5818276 | 지상 9층 | 지상 9층 | 5818108 | 225 | 0.22725 | 0.005454 | 1010
5818287 | 지상 9층 | 지상 9층 | 5818108 | 225 | 0.435375 | 0.010449 | 1935
5818298 | 지상 9층 | 지상 9층 | 5818108 | 225 | 0.423 | 0.010152 | 1880
5818309 | 지상 9층 | 지상 9층 | 5818108 | 225 | 0.423 | 0.010152 | 1880
5818320 | 지상 9층 | 지상 9층 | 5818108 | 225 | 0.423 | 0.010152 | 1880
5818331 | 지상 9층 | 지상 9층 | 5818108 | 225 | 0.228375 | 0.005481 | 1015
5818342 | 지상 9층 | 지상 9층 | 5818108 | 225 | 0.200741 | 0.00481779 | 892.184
5818114 | 지상 9층 | 지상 9층 | 5818108 | 550 | 0.502049 | 0.0120492 | 912.816
5818189 | 지상 9층 | 지상 9층 | 5818108 | 550 | 0.5555 | 0.013332 | 1010
5818211 | 지상 9층 | 지상 9층 | 5818108 | 550 | 0.5555 | 0.013332 | 1010
5818277 | 지상 9층 | 지상 9층 | 5818108 | 550 | 0.5555 | 0.013332 | 1010
5818343 | 지상 9층 | 지상 9층 | 5818108 | 550 | 0.490701 | 0.0117768 | 892.184
5818118 | 지상 9층 | 지상 9층 | 5818108 | 1525 | 1.39205 | 0.0334091 | 912.816
5818124 | 지상 9층 | 지상 9층 | 5818108 | 1525 | 2.91275 | 0.069906 | 1910
5818135 | 지상 9층 | 지상 9층 | 5818108 | 1525 | 2.867 | 0.068808 | 1880
5818146 | 지상 9층 | 지상 9층 | 5818108 | 1525 | 2.867 | 0.068808 | 1880
5818157 | 지상 9층 | 지상 9층 | 5818108 | 1525 | 2.867 | 0.068808 | 1880
5818168 | 지상 9층 | 지상 9층 | 5818108 | 1525 | 2.867 | 0.068808 | 1880
5818179 | 지상 9층 | 지상 9층 | 5818108 | 1525 | 2.91275 | 0.069906 | 1910
5818190 | 지상 9층 | 지상 9층 | 5818108 | 1525 | 1.54025 | 0.036966 | 1010
5818201 | 지상 9층 | 지상 9층 | 5818108 | 1525 | 3.33975 | 0.080154 | 2190
5818212 | 지상 9층 | 지상 9층 | 5818108 | 1525 | 1.54025 | 0.036966 | 1010
5818223 | 지상 9층 | 지상 9층 | 5818108 | 1525 | 2.867 | 0.068808 | 1880
5818234 | 지상 9층 | 지상 9층 | 5818108 | 1525 | 2.867 | 0.068808 | 1880
5818245 | 지상 9층 | 지상 9층 | 5818108 | 1525 | 2.867 | 0.068808 | 1880
5818256 | 지상 9층 | 지상 9층 | 5818108 | 1525 | 2.867 | 0.068808 | 1880
5818267 | 지상 9층 | 지상 9층 | 5818108 | 1525 | 2.85938 | 0.068625 | 1875
5818278 | 지상 9층 | 지상 9층 | 5818108 | 1525 | 1.54025 | 0.036966 | 1010
5818289 | 지상 9층 | 지상 9층 | 5818108 | 1525 | 2.95088 | 0.070821 | 1935
5818300 | 지상 9층 | 지상 9층 | 5818108 | 1525 | 2.867 | 0.068808 | 1880
5818311 | 지상 9층 | 지상 9층 | 5818108 | 1525 | 2.867 | 0.068808 | 1880
5818322 | 지상 9층 | 지상 9층 | 5818108 | 1525 | 2.867 | 0.068808 | 1880
5818333 | 지상 9층 | 지상 9층 | 5818108 | 1525 | 1.54788 | 0.037149 | 1015
5818344 | 지상 9층 | 지상 9층 | 5818108 | 1525 | 1.36058 | 0.0326539 | 892.184
5818682 | 지상 9층 | 지상 9층 | 5818681 | 225 | 0.0401388 | 0.000963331 | 178.395
5818698 | 지상 9층 | 지상 9층 | 5818681 | 225 | 0.372825 | 0.0089478 | 1657
5818709 | 지상 9층 | 지상 9층 | 5818681 | 225 | 0.372825 | 0.0089478 | 1657
5818720 | 지상 9층 | 지상 9층 | 5818681 | 225 | 0.372825 | 0.0089478 | 1657
5818731 | 지상 9층 | 지상 9층 | 5818681 | 225 | 0.372825 | 0.0089478 | 1657
5818742 | 지상 9층 | 지상 9층 | 5818681 | 225 | 0.252 | 0.006048 | 1120
5818753 | 지상 9층 | 지상 9층 | 5818681 | 225 | 0.3393 | 0.0081432 | 1508
5818764 | 지상 9층 | 지상 9층 | 5818681 | 225 | 0.3393 | 0.0081432 | 1508
5818775 | 지상 9층 | 지상 9층 | 5818681 | 225 | 0.3393 | 0.0081432 | 1508
5818786 | 지상 9층 | 지상 9층 | 5818681 | 225 | 0.3393 | 0.0081432 | 1508
5818797 | 지상 9층 | 지상 9층 | 5818681 | 225 | 0.252 | 0.006048 | 1120
5818808 | 지상 9층 | 지상 9층 | 5818681 | 225 | 0.333675 | 0.0080082 | 1483
5818819 | 지상 9층 | 지상 9층 | 5818681 | 225 | 0.333675 | 0.0080082 | 1483
5818830 | 지상 9층 | 지상 9층 | 5818681 | 225 | 0.333675 | 0.0080082 | 1483
5818841 | 지상 9층 | 지상 9층 | 5818681 | 225 | 0.333675 | 0.0080082 | 1483
5818852 | 지상 9층 | 지상 9층 | 5818681 | 225 | 0.252 | 0.006048 | 1120
5818863 | 지상 9층 | 지상 9층 | 5818681 | 225 | 0.334511 | 0.00802826 | 1486.71
5818874 | 지상 9층 | 지상 9층 | 5818681 | 225 | 0.334511 | 0.00802826 | 1486.71
5818885 | 지상 9층 | 지상 9층 | 5818681 | 225 | 0.334511 | 0.00802826 | 1486.71
5818896 | 지상 9층 | 지상 9층 | 5818681 | 225 | 0.334511 | 0.00802826 | 1486.71
5818907 | 지상 9층 | 지상 9층 | 5818681 | 225 | 0.334511 | 0.00802826 | 1486.71
5818918 | 지상 9층 | 지상 9층 | 5818681 | 225 | 0.334511 | 0.00802826 | 1486.71
5818929 | 지상 9층 | 지상 9층 | 5818681 | 225 | 0.334511 | 0.00802826 | 1486.71
5818940 | 지상 9층 | 지상 9층 | 5818681 | 225 | 0.205338 | 0.00492812 | 912.614
5818688 | 지상 9층 | 지상 9층 | 5818681 | 550 | 0.098117 | 0.00235481 | 178.395
5818743 | 지상 9층 | 지상 9층 | 5818681 | 550 | 0.616 | 0.014784 | 1120
5818798 | 지상 9층 | 지상 9층 | 5818681 | 550 | 0.616 | 0.014784 | 1120
5818853 | 지상 9층 | 지상 9층 | 5818681 | 550 | 0.616 | 0.014784 | 1120
5818941 | 지상 9층 | 지상 9층 | 5818681 | 550 | 0.501938 | 0.0120465 | 912.614
5818693 | 지상 9층 | 지상 9층 | 5818681 | 1525 | 0.272052 | 0.00652924 | 178.395
5818700 | 지상 9층 | 지상 9층 | 5818681 | 1525 | 2.52693 | 0.0606462 | 1657
5818711 | 지상 9층 | 지상 9층 | 5818681 | 1525 | 2.52693 | 0.0606462 | 1657
5818722 | 지상 9층 | 지상 9층 | 5818681 | 1525 | 2.52693 | 0.0606462 | 1657
5818733 | 지상 9층 | 지상 9층 | 5818681 | 1525 | 2.52693 | 0.0606462 | 1657
5818744 | 지상 9층 | 지상 9층 | 5818681 | 1525 | 1.708 | 0.040992 | 1120
5818755 | 지상 9층 | 지상 9층 | 5818681 | 1525 | 2.2997 | 0.0551928 | 1508
5818766 | 지상 9층 | 지상 9층 | 5818681 | 1525 | 2.2997 | 0.0551928 | 1508
5818777 | 지상 9층 | 지상 9층 | 5818681 | 1525 | 2.2997 | 0.0551928 | 1508
5818788 | 지상 9층 | 지상 9층 | 5818681 | 1525 | 2.2997 | 0.0551928 | 1508
5818799 | 지상 9층 | 지상 9층 | 5818681 | 1525 | 1.708 | 0.040992 | 1120
5818810 | 지상 9층 | 지상 9층 | 5818681 | 1525 | 2.26158 | 0.0542778 | 1483
5818821 | 지상 9층 | 지상 9층 | 5818681 | 1525 | 2.26158 | 0.0542778 | 1483
5818832 | 지상 9층 | 지상 9층 | 5818681 | 1525 | 2.26158 | 0.0542778 | 1483
5818843 | 지상 9층 | 지상 9층 | 5818681 | 1525 | 2.26158 | 0.0542778 | 1483
5818854 | 지상 9층 | 지상 9층 | 5818681 | 1525 | 1.708 | 0.040992 | 1120
5818865 | 지상 9층 | 지상 9층 | 5818681 | 1525 | 2.26724 | 0.0544137 | 1486.71
5818876 | 지상 9층 | 지상 9층 | 5818681 | 1525 | 2.26724 | 0.0544137 | 1486.71
5818887 | 지상 9층 | 지상 9층 | 5818681 | 1525 | 2.26724 | 0.0544137 | 1486.71
5818898 | 지상 9층 | 지상 9층 | 5818681 | 1525 | 2.26724 | 0.0544137 | 1486.71
5818909 | 지상 9층 | 지상 9층 | 5818681 | 1525 | 2.26724 | 0.0544137 | 1486.71
5818920 | 지상 9층 | 지상 9층 | 5818681 | 1525 | 2.26724 | 0.0544137 | 1486.71
5818931 | 지상 9층 | 지상 9층 | 5818681 | 1525 | 2.26724 | 0.0544137 | 1486.71
5818942 | 지상 9층 | 지상 9층 | 5818681 | 1525 | 1.39174 | 0.0334017 | 912.614
5819255 | 지상 8층 | 지상 8층 | 5819254 | 225 | 0.205384 | 0.00492921 | 912.816
5819268 | 지상 8층 | 지상 8층 | 5819254 | 225 | 0.42975 | 0.010314 | 1910
5819279 | 지상 8층 | 지상 8층 | 5819254 | 225 | 0.423 | 0.010152 | 1880
5819290 | 지상 8층 | 지상 8층 | 5819254 | 225 | 0.423 | 0.010152 | 1880
5819301 | 지상 8층 | 지상 8층 | 5819254 | 225 | 0.423 | 0.010152 | 1880
5819312 | 지상 8층 | 지상 8층 | 5819254 | 225 | 0.423 | 0.010152 | 1880
5819323 | 지상 8층 | 지상 8층 | 5819254 | 225 | 0.42975 | 0.010314 | 1910
5819334 | 지상 8층 | 지상 8층 | 5819254 | 225 | 0.22725 | 0.005454 | 1010
5819345 | 지상 8층 | 지상 8층 | 5819254 | 225 | 0.49275 | 0.011826 | 2190
5819356 | 지상 8층 | 지상 8층 | 5819254 | 225 | 0.22725 | 0.005454 | 1010
5819367 | 지상 8층 | 지상 8층 | 5819254 | 225 | 0.423 | 0.010152 | 1880
5819378 | 지상 8층 | 지상 8층 | 5819254 | 225 | 0.423 | 0.010152 | 1880
5819389 | 지상 8층 | 지상 8층 | 5819254 | 225 | 0.423 | 0.010152 | 1880
5819400 | 지상 8층 | 지상 8층 | 5819254 | 225 | 0.423 | 0.010152 | 1880
5819411 | 지상 8층 | 지상 8층 | 5819254 | 225 | 0.421875 | 0.010125 | 1875
5819422 | 지상 8층 | 지상 8층 | 5819254 | 225 | 0.22725 | 0.005454 | 1010
5819433 | 지상 8층 | 지상 8층 | 5819254 | 225 | 0.435375 | 0.010449 | 1935
5819444 | 지상 8층 | 지상 8층 | 5819254 | 225 | 0.423 | 0.010152 | 1880
5819455 | 지상 8층 | 지상 8층 | 5819254 | 225 | 0.423 | 0.010152 | 1880
5819466 | 지상 8층 | 지상 8층 | 5819254 | 225 | 0.423 | 0.010152 | 1880
5819477 | 지상 8층 | 지상 8층 | 5819254 | 225 | 0.228375 | 0.005481 | 1015
5819488 | 지상 8층 | 지상 8층 | 5819254 | 225 | 0.200879 | 0.00482109 | 892.794
5819260 | 지상 8층 | 지상 8층 | 5819254 | 550 | 0.502049 | 0.0120492 | 912.816
5819335 | 지상 8층 | 지상 8층 | 5819254 | 550 | 0.5555 | 0.013332 | 1010
5819357 | 지상 8층 | 지상 8층 | 5819254 | 550 | 0.5555 | 0.013332 | 1010
5819423 | 지상 8층 | 지상 8층 | 5819254 | 550 | 0.5555 | 0.013332 | 1010
5819489 | 지상 8층 | 지상 8층 | 5819254 | 550 | 0.491037 | 0.0117849 | 892.794
5819264 | 지상 8층 | 지상 8층 | 5819254 | 1025 | 0.935637 | 0.0224553 | 912.816
5819270 | 지상 8층 | 지상 8층 | 5819254 | 1025 | 1.95775 | 0.046986 | 1910
5819281 | 지상 8층 | 지상 8층 | 5819254 | 1025 | 1.927 | 0.046248 | 1880
5819292 | 지상 8층 | 지상 8층 | 5819254 | 1025 | 1.927 | 0.046248 | 1880
5819303 | 지상 8층 | 지상 8층 | 5819254 | 1025 | 1.927 | 0.046248 | 1880
5819314 | 지상 8층 | 지상 8층 | 5819254 | 1025 | 1.927 | 0.046248 | 1880
5819325 | 지상 8층 | 지상 8층 | 5819254 | 1025 | 1.95775 | 0.046986 | 1910
5819336 | 지상 8층 | 지상 8층 | 5819254 | 1025 | 1.03525 | 0.024846 | 1010
5819347 | 지상 8층 | 지상 8층 | 5819254 | 1025 | 2.24475 | 0.053874 | 2190
5819358 | 지상 8층 | 지상 8층 | 5819254 | 1025 | 1.03525 | 0.024846 | 1010
5819369 | 지상 8층 | 지상 8층 | 5819254 | 1025 | 1.927 | 0.046248 | 1880
5819380 | 지상 8층 | 지상 8층 | 5819254 | 1025 | 1.927 | 0.046248 | 1880
5819391 | 지상 8층 | 지상 8층 | 5819254 | 1025 | 1.927 | 0.046248 | 1880
5819402 | 지상 8층 | 지상 8층 | 5819254 | 1025 | 1.927 | 0.046248 | 1880
5819413 | 지상 8층 | 지상 8층 | 5819254 | 1025 | 1.92187 | 0.046125 | 1875
5819424 | 지상 8층 | 지상 8층 | 5819254 | 1025 | 1.03525 | 0.024846 | 1010
5819435 | 지상 8층 | 지상 8층 | 5819254 | 1025 | 1.98337 | 0.047601 | 1935
5819446 | 지상 8층 | 지상 8층 | 5819254 | 1025 | 1.927 | 0.046248 | 1880
5819457 | 지상 8층 | 지상 8층 | 5819254 | 1025 | 1.927 | 0.046248 | 1880
5819468 | 지상 8층 | 지상 8층 | 5819254 | 1025 | 1.927 | 0.046248 | 1880
5819479 | 지상 8층 | 지상 8층 | 5819254 | 1025 | 1.04038 | 0.024969 | 1015
5819490 | 지상 8층 | 지상 8층 | 5819254 | 1025 | 0.915114 | 0.0219627 | 892.794
5819643 | 지상 8층 | 지상 8층 | 5819642 | 225 | 0.0401388 | 0.000963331 | 178.395
5819659 | 지상 8층 | 지상 8층 | 5819642 | 225 | 0.372825 | 0.0089478 | 1657
5819670 | 지상 8층 | 지상 8층 | 5819642 | 225 | 0.372825 | 0.0089478 | 1657
5819681 | 지상 8층 | 지상 8층 | 5819642 | 225 | 0.372825 | 0.0089478 | 1657
5819692 | 지상 8층 | 지상 8층 | 5819642 | 225 | 0.372825 | 0.0089478 | 1657
5819703 | 지상 8층 | 지상 8층 | 5819642 | 225 | 0.252 | 0.006048 | 1120
5819714 | 지상 8층 | 지상 8층 | 5819642 | 225 | 0.3393 | 0.0081432 | 1508
5819725 | 지상 8층 | 지상 8층 | 5819642 | 225 | 0.3393 | 0.0081432 | 1508
5819736 | 지상 8층 | 지상 8층 | 5819642 | 225 | 0.3393 | 0.0081432 | 1508
5819747 | 지상 8층 | 지상 8층 | 5819642 | 225 | 0.3393 | 0.0081432 | 1508
5819758 | 지상 8층 | 지상 8층 | 5819642 | 225 | 0.252 | 0.006048 | 1120
5819769 | 지상 8층 | 지상 8층 | 5819642 | 225 | 0.333675 | 0.0080082 | 1483
5819780 | 지상 8층 | 지상 8층 | 5819642 | 225 | 0.333675 | 0.0080082 | 1483
5819791 | 지상 8층 | 지상 8층 | 5819642 | 225 | 0.333675 | 0.0080082 | 1483
5819802 | 지상 8층 | 지상 8층 | 5819642 | 225 | 0.333675 | 0.0080082 | 1483
5819813 | 지상 8층 | 지상 8층 | 5819642 | 225 | 0.252 | 0.006048 | 1120
5819824 | 지상 8층 | 지상 8층 | 5819642 | 225 | 0.334511 | 0.00802826 | 1486.71
5819835 | 지상 8층 | 지상 8층 | 5819642 | 225 | 0.334511 | 0.00802826 | 1486.71
5819846 | 지상 8층 | 지상 8층 | 5819642 | 225 | 0.334511 | 0.00802826 | 1486.71
5819857 | 지상 8층 | 지상 8층 | 5819642 | 225 | 0.334511 | 0.00802826 | 1486.71
5819868 | 지상 8층 | 지상 8층 | 5819642 | 225 | 0.334511 | 0.00802826 | 1486.71
5819879 | 지상 8층 | 지상 8층 | 5819642 | 225 | 0.334511 | 0.00802826 | 1486.71
5819890 | 지상 8층 | 지상 8층 | 5819642 | 225 | 0.334511 | 0.00802826 | 1486.71
5819901 | 지상 8층 | 지상 8층 | 5819642 | 225 | 0.20536 | 0.00492863 | 912.71
5819649 | 지상 8층 | 지상 8층 | 5819642 | 550 | 0.098117 | 0.00235481 | 178.395
5819704 | 지상 8층 | 지상 8층 | 5819642 | 550 | 0.616 | 0.014784 | 1120
5819759 | 지상 8층 | 지상 8층 | 5819642 | 550 | 0.616 | 0.014784 | 1120
5819814 | 지상 8층 | 지상 8층 | 5819642 | 550 | 0.616 | 0.014784 | 1120
5819902 | 지상 8층 | 지상 8층 | 5819642 | 550 | 0.50199 | 0.0120478 | 912.71
5819654 | 지상 8층 | 지상 8층 | 5819642 | 1025 | 0.182854 | 0.00438851 | 178.395
5819661 | 지상 8층 | 지상 8층 | 5819642 | 1025 | 1.69842 | 0.0407622 | 1657
5819672 | 지상 8층 | 지상 8층 | 5819642 | 1025 | 1.69842 | 0.0407622 | 1657
5819683 | 지상 8층 | 지상 8층 | 5819642 | 1025 | 1.69842 | 0.0407622 | 1657
5819694 | 지상 8층 | 지상 8층 | 5819642 | 1025 | 1.69842 | 0.0407622 | 1657
5819705 | 지상 8층 | 지상 8층 | 5819642 | 1025 | 1.148 | 0.027552 | 1120
5819716 | 지상 8층 | 지상 8층 | 5819642 | 1025 | 1.5457 | 0.0370968 | 1508
5819727 | 지상 8층 | 지상 8층 | 5819642 | 1025 | 1.5457 | 0.0370968 | 1508
5819738 | 지상 8층 | 지상 8층 | 5819642 | 1025 | 1.5457 | 0.0370968 | 1508
5819749 | 지상 8층 | 지상 8층 | 5819642 | 1025 | 1.5457 | 0.0370968 | 1508
5819760 | 지상 8층 | 지상 8층 | 5819642 | 1025 | 1.148 | 0.027552 | 1120
5819771 | 지상 8층 | 지상 8층 | 5819642 | 1025 | 1.52007 | 0.0364818 | 1483
5819782 | 지상 8층 | 지상 8층 | 5819642 | 1025 | 1.52007 | 0.0364818 | 1483
5819793 | 지상 8층 | 지상 8층 | 5819642 | 1025 | 1.52007 | 0.0364818 | 1483
5819804 | 지상 8층 | 지상 8층 | 5819642 | 1025 | 1.52007 | 0.0364818 | 1483
5819815 | 지상 8층 | 지상 8층 | 5819642 | 1025 | 1.148 | 0.027552 | 1120
5819826 | 지상 8층 | 지상 8층 | 5819642 | 1025 | 1.52388 | 0.0365732 | 1486.71
5819837 | 지상 8층 | 지상 8층 | 5819642 | 1025 | 1.52388 | 0.0365732 | 1486.71
5819848 | 지상 8층 | 지상 8층 | 5819642 | 1025 | 1.52388 | 0.0365732 | 1486.71
5819859 | 지상 8층 | 지상 8층 | 5819642 | 1025 | 1.52388 | 0.0365732 | 1486.71
5819870 | 지상 8층 | 지상 8층 | 5819642 | 1025 | 1.52388 | 0.0365732 | 1486.71
5819881 | 지상 8층 | 지상 8층 | 5819642 | 1025 | 1.52388 | 0.0365732 | 1486.71
5819892 | 지상 8층 | 지상 8층 | 5819642 | 1025 | 1.52388 | 0.0365732 | 1486.71
5819903 | 지상 8층 | 지상 8층 | 5819642 | 1025 | 0.935528 | 0.0224527 | 912.71
5820122 | 지상 7층 | 지상 7층 | 5820121 | 225 | 0.205384 | 0.00492921 | 912.816
5820135 | 지상 7층 | 지상 7층 | 5820121 | 225 | 0.42975 | 0.010314 | 1910
5820146 | 지상 7층 | 지상 7층 | 5820121 | 225 | 0.423 | 0.010152 | 1880
5820157 | 지상 7층 | 지상 7층 | 5820121 | 225 | 0.423 | 0.010152 | 1880
5820168 | 지상 7층 | 지상 7층 | 5820121 | 225 | 0.423 | 0.010152 | 1880
5820179 | 지상 7층 | 지상 7층 | 5820121 | 225 | 0.423 | 0.010152 | 1880
5820190 | 지상 7층 | 지상 7층 | 5820121 | 225 | 0.42975 | 0.010314 | 1910
5820201 | 지상 7층 | 지상 7층 | 5820121 | 225 | 0.22725 | 0.005454 | 1010
5820212 | 지상 7층 | 지상 7층 | 5820121 | 225 | 0.49275 | 0.011826 | 2190
5820223 | 지상 7층 | 지상 7층 | 5820121 | 225 | 0.22725 | 0.005454 | 1010
5820234 | 지상 7층 | 지상 7층 | 5820121 | 225 | 0.423 | 0.010152 | 1880
5820245 | 지상 7층 | 지상 7층 | 5820121 | 225 | 0.423 | 0.010152 | 1880
5820256 | 지상 7층 | 지상 7층 | 5820121 | 225 | 0.423 | 0.010152 | 1880
5820267 | 지상 7층 | 지상 7층 | 5820121 | 225 | 0.423 | 0.010152 | 1880
5820278 | 지상 7층 | 지상 7층 | 5820121 | 225 | 0.421875 | 0.010125 | 1875
5820289 | 지상 7층 | 지상 7층 | 5820121 | 225 | 0.22725 | 0.005454 | 1010
5820300 | 지상 7층 | 지상 7층 | 5820121 | 225 | 0.435375 | 0.010449 | 1935
5820311 | 지상 7층 | 지상 7층 | 5820121 | 225 | 0.423 | 0.010152 | 1880
5820322 | 지상 7층 | 지상 7층 | 5820121 | 225 | 0.423 | 0.010152 | 1880
5820333 | 지상 7층 | 지상 7층 | 5820121 | 225 | 0.423 | 0.010152 | 1880
5820344 | 지상 7층 | 지상 7층 | 5820121 | 225 | 0.228375 | 0.005481 | 1015
5820355 | 지상 7층 | 지상 7층 | 5820121 | 225 | 0.200741 | 0.00481779 | 892.184
5820127 | 지상 7층 | 지상 7층 | 5820121 | 550 | 0.502049 | 0.0120492 | 912.816
5820202 | 지상 7층 | 지상 7층 | 5820121 | 550 | 0.5555 | 0.013332 | 1010
5820224 | 지상 7층 | 지상 7층 | 5820121 | 550 | 0.5555 | 0.013332 | 1010
5820290 | 지상 7층 | 지상 7층 | 5820121 | 550 | 0.5555 | 0.013332 | 1010
5820356 | 지상 7층 | 지상 7층 | 5820121 | 550 | 0.490701 | 0.0117768 | 892.184
5820131 | 지상 7층 | 지상 7층 | 5820121 | 1025 | 0.935637 | 0.0224553 | 912.816
5820137 | 지상 7층 | 지상 7층 | 5820121 | 1025 | 1.95775 | 0.046986 | 1910
5820148 | 지상 7층 | 지상 7층 | 5820121 | 1025 | 1.927 | 0.046248 | 1880
5820159 | 지상 7층 | 지상 7층 | 5820121 | 1025 | 1.927 | 0.046248 | 1880
5820170 | 지상 7층 | 지상 7층 | 5820121 | 1025 | 1.927 | 0.046248 | 1880
5820181 | 지상 7층 | 지상 7층 | 5820121 | 1025 | 1.927 | 0.046248 | 1880
5820192 | 지상 7층 | 지상 7층 | 5820121 | 1025 | 1.95775 | 0.046986 | 1910
5820203 | 지상 7층 | 지상 7층 | 5820121 | 1025 | 1.03525 | 0.024846 | 1010
5820214 | 지상 7층 | 지상 7층 | 5820121 | 1025 | 2.24475 | 0.053874 | 2190
5820225 | 지상 7층 | 지상 7층 | 5820121 | 1025 | 1.03525 | 0.024846 | 1010
5820236 | 지상 7층 | 지상 7층 | 5820121 | 1025 | 1.927 | 0.046248 | 1880
5820247 | 지상 7층 | 지상 7층 | 5820121 | 1025 | 1.927 | 0.046248 | 1880
5820258 | 지상 7층 | 지상 7층 | 5820121 | 1025 | 1.927 | 0.046248 | 1880
5820269 | 지상 7층 | 지상 7층 | 5820121 | 1025 | 1.927 | 0.046248 | 1880
5820280 | 지상 7층 | 지상 7층 | 5820121 | 1025 | 1.92187 | 0.046125 | 1875
5820291 | 지상 7층 | 지상 7층 | 5820121 | 1025 | 1.03525 | 0.024846 | 1010
5820302 | 지상 7층 | 지상 7층 | 5820121 | 1025 | 1.98337 | 0.047601 | 1935
5820313 | 지상 7층 | 지상 7층 | 5820121 | 1025 | 1.927 | 0.046248 | 1880
5820324 | 지상 7층 | 지상 7층 | 5820121 | 1025 | 1.927 | 0.046248 | 1880
5820335 | 지상 7층 | 지상 7층 | 5820121 | 1025 | 1.927 | 0.046248 | 1880
5820346 | 지상 7층 | 지상 7층 | 5820121 | 1025 | 1.04038 | 0.024969 | 1015
5820357 | 지상 7층 | 지상 7층 | 5820121 | 1025 | 0.914488 | 0.0219477 | 892.184
5820510 | 지상 7층 | 지상 7층 | 5820509 | 225 | 0.0401388 | 0.000963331 | 178.395
5820526 | 지상 7층 | 지상 7층 | 5820509 | 225 | 0.372825 | 0.0089478 | 1657
5820537 | 지상 7층 | 지상 7층 | 5820509 | 225 | 0.372825 | 0.0089478 | 1657
5820548 | 지상 7층 | 지상 7층 | 5820509 | 225 | 0.372825 | 0.0089478 | 1657
5820559 | 지상 7층 | 지상 7층 | 5820509 | 225 | 0.372825 | 0.0089478 | 1657
5820570 | 지상 7층 | 지상 7층 | 5820509 | 225 | 0.252 | 0.006048 | 1120
5820581 | 지상 7층 | 지상 7층 | 5820509 | 225 | 0.3393 | 0.0081432 | 1508
5820592 | 지상 7층 | 지상 7층 | 5820509 | 225 | 0.3393 | 0.0081432 | 1508
5820603 | 지상 7층 | 지상 7층 | 5820509 | 225 | 0.3393 | 0.0081432 | 1508
5820614 | 지상 7층 | 지상 7층 | 5820509 | 225 | 0.3393 | 0.0081432 | 1508
5820625 | 지상 7층 | 지상 7층 | 5820509 | 225 | 0.252 | 0.006048 | 1120
5820636 | 지상 7층 | 지상 7층 | 5820509 | 225 | 0.333675 | 0.0080082 | 1483
5820647 | 지상 7층 | 지상 7층 | 5820509 | 225 | 0.333675 | 0.0080082 | 1483
5820658 | 지상 7층 | 지상 7층 | 5820509 | 225 | 0.333675 | 0.0080082 | 1483
5820669 | 지상 7층 | 지상 7층 | 5820509 | 225 | 0.333675 | 0.0080082 | 1483
5820680 | 지상 7층 | 지상 7층 | 5820509 | 225 | 0.252 | 0.006048 | 1120
5820691 | 지상 7층 | 지상 7층 | 5820509 | 225 | 0.334511 | 0.00802826 | 1486.71
5820702 | 지상 7층 | 지상 7층 | 5820509 | 225 | 0.334511 | 0.00802826 | 1486.71
5820713 | 지상 7층 | 지상 7층 | 5820509 | 225 | 0.334511 | 0.00802826 | 1486.71
5820724 | 지상 7층 | 지상 7층 | 5820509 | 225 | 0.334511 | 0.00802826 | 1486.71
5820735 | 지상 7층 | 지상 7층 | 5820509 | 225 | 0.334511 | 0.00802826 | 1486.71
5820746 | 지상 7층 | 지상 7층 | 5820509 | 225 | 0.334511 | 0.00802826 | 1486.71
5820757 | 지상 7층 | 지상 7층 | 5820509 | 225 | 0.334511 | 0.00802826 | 1486.71
5820768 | 지상 7층 | 지상 7층 | 5820509 | 225 | 0.205298 | 0.00492716 | 912.437
5820516 | 지상 7층 | 지상 7층 | 5820509 | 550 | 0.098117 | 0.00235481 | 178.395
5820571 | 지상 7층 | 지상 7층 | 5820509 | 550 | 0.616 | 0.014784 | 1120
5820626 | 지상 7층 | 지상 7층 | 5820509 | 550 | 0.616 | 0.014784 | 1120
5820681 | 지상 7층 | 지상 7층 | 5820509 | 550 | 0.616 | 0.014784 | 1120
5820769 | 지상 7층 | 지상 7층 | 5820509 | 550 | 0.50184 | 0.0120442 | 912.437
5820521 | 지상 7층 | 지상 7층 | 5820509 | 1025 | 0.182854 | 0.00438851 | 178.395
5820528 | 지상 7층 | 지상 7층 | 5820509 | 1025 | 1.69842 | 0.0407622 | 1657
5820539 | 지상 7층 | 지상 7층 | 5820509 | 1025 | 1.69842 | 0.0407622 | 1657
5820550 | 지상 7층 | 지상 7층 | 5820509 | 1025 | 1.69842 | 0.0407622 | 1657
5820561 | 지상 7층 | 지상 7층 | 5820509 | 1025 | 1.69842 | 0.0407622 | 1657
5820572 | 지상 7층 | 지상 7층 | 5820509 | 1025 | 1.148 | 0.027552 | 1120
5820583 | 지상 7층 | 지상 7층 | 5820509 | 1025 | 1.5457 | 0.0370968 | 1508
5820594 | 지상 7층 | 지상 7층 | 5820509 | 1025 | 1.5457 | 0.0370968 | 1508
5820605 | 지상 7층 | 지상 7층 | 5820509 | 1025 | 1.5457 | 0.0370968 | 1508
5820616 | 지상 7층 | 지상 7층 | 5820509 | 1025 | 1.5457 | 0.0370968 | 1508
5820627 | 지상 7층 | 지상 7층 | 5820509 | 1025 | 1.148 | 0.027552 | 1120
5820638 | 지상 7층 | 지상 7층 | 5820509 | 1025 | 1.52007 | 0.0364818 | 1483
5820649 | 지상 7층 | 지상 7층 | 5820509 | 1025 | 1.52007 | 0.0364818 | 1483
5820660 | 지상 7층 | 지상 7층 | 5820509 | 1025 | 1.52007 | 0.0364818 | 1483
5820671 | 지상 7층 | 지상 7층 | 5820509 | 1025 | 1.52007 | 0.0364818 | 1483
5820682 | 지상 7층 | 지상 7층 | 5820509 | 1025 | 1.148 | 0.027552 | 1120
5820693 | 지상 7층 | 지상 7층 | 5820509 | 1025 | 1.52388 | 0.0365732 | 1486.71
5820704 | 지상 7층 | 지상 7층 | 5820509 | 1025 | 1.52388 | 0.0365732 | 1486.71
5820715 | 지상 7층 | 지상 7층 | 5820509 | 1025 | 1.52388 | 0.0365732 | 1486.71
5820726 | 지상 7층 | 지상 7층 | 5820509 | 1025 | 1.52388 | 0.0365732 | 1486.71
5820737 | 지상 7층 | 지상 7층 | 5820509 | 1025 | 1.52388 | 0.0365732 | 1486.71
5820748 | 지상 7층 | 지상 7층 | 5820509 | 1025 | 1.52388 | 0.0365732 | 1486.71
5820759 | 지상 7층 | 지상 7층 | 5820509 | 1025 | 1.52388 | 0.0365732 | 1486.71
5820770 | 지상 7층 | 지상 7층 | 5820509 | 1025 | 0.935248 | 0.0224459 | 912.437
5821010 | 지상 6층 | 지상 6층 | 5821009 | 225 | 0.205384 | 0.00492921 | 912.816
5821023 | 지상 6층 | 지상 6층 | 5821009 | 225 | 0.42975 | 0.010314 | 1910
5821034 | 지상 6층 | 지상 6층 | 5821009 | 225 | 0.423 | 0.010152 | 1880
5821045 | 지상 6층 | 지상 6층 | 5821009 | 225 | 0.423 | 0.010152 | 1880
5821056 | 지상 6층 | 지상 6층 | 5821009 | 225 | 0.423 | 0.010152 | 1880
5821067 | 지상 6층 | 지상 6층 | 5821009 | 225 | 0.423 | 0.010152 | 1880
5821078 | 지상 6층 | 지상 6층 | 5821009 | 225 | 0.42975 | 0.010314 | 1910
5821089 | 지상 6층 | 지상 6층 | 5821009 | 225 | 0.22725 | 0.005454 | 1010
5821100 | 지상 6층 | 지상 6층 | 5821009 | 225 | 0.49275 | 0.011826 | 2190
5821111 | 지상 6층 | 지상 6층 | 5821009 | 225 | 0.22725 | 0.005454 | 1010
5821122 | 지상 6층 | 지상 6층 | 5821009 | 225 | 0.423 | 0.010152 | 1880
5821133 | 지상 6층 | 지상 6층 | 5821009 | 225 | 0.423 | 0.010152 | 1880
5821144 | 지상 6층 | 지상 6층 | 5821009 | 225 | 0.423 | 0.010152 | 1880
5821155 | 지상 6층 | 지상 6층 | 5821009 | 225 | 0.423 | 0.010152 | 1880
5821166 | 지상 6층 | 지상 6층 | 5821009 | 225 | 0.421875 | 0.010125 | 1875
5821177 | 지상 6층 | 지상 6층 | 5821009 | 225 | 0.22725 | 0.005454 | 1010
5821188 | 지상 6층 | 지상 6층 | 5821009 | 225 | 0.435375 | 0.010449 | 1935
5821199 | 지상 6층 | 지상 6층 | 5821009 | 225 | 0.423 | 0.010152 | 1880
5821210 | 지상 6층 | 지상 6층 | 5821009 | 225 | 0.423 | 0.010152 | 1880
5821221 | 지상 6층 | 지상 6층 | 5821009 | 225 | 0.423 | 0.010152 | 1880
5821232 | 지상 6층 | 지상 6층 | 5821009 | 225 | 0.228375 | 0.005481 | 1015
5821243 | 지상 6층 | 지상 6층 | 5821009 | 225 | 0.200741 | 0.00481779 | 892.184
5821015 | 지상 6층 | 지상 6층 | 5821009 | 550 | 0.502049 | 0.0120492 | 912.816
5821090 | 지상 6층 | 지상 6층 | 5821009 | 550 | 0.5555 | 0.013332 | 1010
5821112 | 지상 6층 | 지상 6층 | 5821009 | 550 | 0.5555 | 0.013332 | 1010
5821178 | 지상 6층 | 지상 6층 | 5821009 | 550 | 0.5555 | 0.013332 | 1010
5821244 | 지상 6층 | 지상 6층 | 5821009 | 550 | 0.490701 | 0.0117768 | 892.184
5821019 | 지상 6층 | 지상 6층 | 5821009 | 1025 | 0.935637 | 0.0224553 | 912.816
5821025 | 지상 6층 | 지상 6층 | 5821009 | 1025 | 1.95775 | 0.046986 | 1910
5821036 | 지상 6층 | 지상 6층 | 5821009 | 1025 | 1.927 | 0.046248 | 1880
5821047 | 지상 6층 | 지상 6층 | 5821009 | 1025 | 1.927 | 0.046248 | 1880
5821058 | 지상 6층 | 지상 6층 | 5821009 | 1025 | 1.927 | 0.046248 | 1880
5821069 | 지상 6층 | 지상 6층 | 5821009 | 1025 | 1.927 | 0.046248 | 1880
5821080 | 지상 6층 | 지상 6층 | 5821009 | 1025 | 1.95775 | 0.046986 | 1910
5821091 | 지상 6층 | 지상 6층 | 5821009 | 1025 | 1.03525 | 0.024846 | 1010
5821102 | 지상 6층 | 지상 6층 | 5821009 | 1025 | 2.24475 | 0.053874 | 2190
5821113 | 지상 6층 | 지상 6층 | 5821009 | 1025 | 1.03525 | 0.024846 | 1010
5821124 | 지상 6층 | 지상 6층 | 5821009 | 1025 | 1.927 | 0.046248 | 1880
5821135 | 지상 6층 | 지상 6층 | 5821009 | 1025 | 1.927 | 0.046248 | 1880
5821146 | 지상 6층 | 지상 6층 | 5821009 | 1025 | 1.927 | 0.046248 | 1880
5821157 | 지상 6층 | 지상 6층 | 5821009 | 1025 | 1.927 | 0.046248 | 1880
5821168 | 지상 6층 | 지상 6층 | 5821009 | 1025 | 1.92187 | 0.046125 | 1875
5821179 | 지상 6층 | 지상 6층 | 5821009 | 1025 | 1.03525 | 0.024846 | 1010
5821190 | 지상 6층 | 지상 6층 | 5821009 | 1025 | 1.98337 | 0.047601 | 1935
5821201 | 지상 6층 | 지상 6층 | 5821009 | 1025 | 1.927 | 0.046248 | 1880
5821212 | 지상 6층 | 지상 6층 | 5821009 | 1025 | 1.927 | 0.046248 | 1880
5821223 | 지상 6층 | 지상 6층 | 5821009 | 1025 | 1.927 | 0.046248 | 1880
5821234 | 지상 6층 | 지상 6층 | 5821009 | 1025 | 1.04038 | 0.024969 | 1015
5821245 | 지상 6층 | 지상 6층 | 5821009 | 1025 | 0.914488 | 0.0219477 | 892.184
5821398 | 지상 6층 | 지상 6층 | 5821397 | 225 | 0.0401388 | 0.000963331 | 178.395
5821414 | 지상 6층 | 지상 6층 | 5821397 | 225 | 0.372825 | 0.0089478 | 1657
5821425 | 지상 6층 | 지상 6층 | 5821397 | 225 | 0.372825 | 0.0089478 | 1657
5821436 | 지상 6층 | 지상 6층 | 5821397 | 225 | 0.372825 | 0.0089478 | 1657
5821447 | 지상 6층 | 지상 6층 | 5821397 | 225 | 0.372825 | 0.0089478 | 1657
5821458 | 지상 6층 | 지상 6층 | 5821397 | 225 | 0.252 | 0.006048 | 1120
5821469 | 지상 6층 | 지상 6층 | 5821397 | 225 | 0.3393 | 0.0081432 | 1508
5821480 | 지상 6층 | 지상 6층 | 5821397 | 225 | 0.3393 | 0.0081432 | 1508
5821491 | 지상 6층 | 지상 6층 | 5821397 | 225 | 0.3393 | 0.0081432 | 1508
5821502 | 지상 6층 | 지상 6층 | 5821397 | 225 | 0.3393 | 0.0081432 | 1508
5821513 | 지상 6층 | 지상 6층 | 5821397 | 225 | 0.252 | 0.006048 | 1120
5821524 | 지상 6층 | 지상 6층 | 5821397 | 225 | 0.333675 | 0.0080082 | 1483
5821535 | 지상 6층 | 지상 6층 | 5821397 | 225 | 0.333675 | 0.0080082 | 1483
5821546 | 지상 6층 | 지상 6층 | 5821397 | 225 | 0.333675 | 0.0080082 | 1483
5821557 | 지상 6층 | 지상 6층 | 5821397 | 225 | 0.333675 | 0.0080082 | 1483
5821568 | 지상 6층 | 지상 6층 | 5821397 | 225 | 0.252 | 0.006048 | 1120
5821579 | 지상 6층 | 지상 6층 | 5821397 | 225 | 0.334511 | 0.00802826 | 1486.71
5821590 | 지상 6층 | 지상 6층 | 5821397 | 225 | 0.334511 | 0.00802826 | 1486.71
5821601 | 지상 6층 | 지상 6층 | 5821397 | 225 | 0.334511 | 0.00802826 | 1486.71
5821612 | 지상 6층 | 지상 6층 | 5821397 | 225 | 0.334511 | 0.00802826 | 1486.71
5821623 | 지상 6층 | 지상 6층 | 5821397 | 225 | 0.334511 | 0.00802826 | 1486.71
5821634 | 지상 6층 | 지상 6층 | 5821397 | 225 | 0.334511 | 0.00802826 | 1486.71
5821645 | 지상 6층 | 지상 6층 | 5821397 | 225 | 0.334511 | 0.00802826 | 1486.71
5821656 | 지상 6층 | 지상 6층 | 5821397 | 225 | 0.205346 | 0.0049283 | 912.649
5821404 | 지상 6층 | 지상 6층 | 5821397 | 550 | 0.098117 | 0.00235481 | 178.395
5821459 | 지상 6층 | 지상 6층 | 5821397 | 550 | 0.616 | 0.014784 | 1120
5821514 | 지상 6층 | 지상 6층 | 5821397 | 550 | 0.616 | 0.014784 | 1120
5821569 | 지상 6층 | 지상 6층 | 5821397 | 550 | 0.616 | 0.014784 | 1120
5821657 | 지상 6층 | 지상 6층 | 5821397 | 550 | 0.501957 | 0.012047 | 912.649
5821409 | 지상 6층 | 지상 6층 | 5821397 | 1025 | 0.182854 | 0.00438851 | 178.395
5821416 | 지상 6층 | 지상 6층 | 5821397 | 1025 | 1.69842 | 0.0407622 | 1657
5821427 | 지상 6층 | 지상 6층 | 5821397 | 1025 | 1.69842 | 0.0407622 | 1657
5821438 | 지상 6층 | 지상 6층 | 5821397 | 1025 | 1.69842 | 0.0407622 | 1657
5821449 | 지상 6층 | 지상 6층 | 5821397 | 1025 | 1.69842 | 0.0407622 | 1657
5821460 | 지상 6층 | 지상 6층 | 5821397 | 1025 | 1.148 | 0.027552 | 1120
5821471 | 지상 6층 | 지상 6층 | 5821397 | 1025 | 1.5457 | 0.0370968 | 1508
5821482 | 지상 6층 | 지상 6층 | 5821397 | 1025 | 1.5457 | 0.0370968 | 1508
5821493 | 지상 6층 | 지상 6층 | 5821397 | 1025 | 1.5457 | 0.0370968 | 1508
5821504 | 지상 6층 | 지상 6층 | 5821397 | 1025 | 1.5457 | 0.0370968 | 1508
5821515 | 지상 6층 | 지상 6층 | 5821397 | 1025 | 1.148 | 0.027552 | 1120
5821526 | 지상 6층 | 지상 6층 | 5821397 | 1025 | 1.52007 | 0.0364818 | 1483
5821537 | 지상 6층 | 지상 6층 | 5821397 | 1025 | 1.52007 | 0.0364818 | 1483
5821548 | 지상 6층 | 지상 6층 | 5821397 | 1025 | 1.52007 | 0.0364818 | 1483
5821559 | 지상 6층 | 지상 6층 | 5821397 | 1025 | 1.52007 | 0.0364818 | 1483
5821570 | 지상 6층 | 지상 6층 | 5821397 | 1025 | 1.148 | 0.027552 | 1120
5821581 | 지상 6층 | 지상 6층 | 5821397 | 1025 | 1.52388 | 0.0365732 | 1486.71
5821592 | 지상 6층 | 지상 6층 | 5821397 | 1025 | 1.52388 | 0.0365732 | 1486.71
5821603 | 지상 6층 | 지상 6층 | 5821397 | 1025 | 1.52388 | 0.0365732 | 1486.71
5821614 | 지상 6층 | 지상 6층 | 5821397 | 1025 | 1.52388 | 0.0365732 | 1486.71
5821625 | 지상 6층 | 지상 6층 | 5821397 | 1025 | 1.52388 | 0.0365732 | 1486.71
5821636 | 지상 6층 | 지상 6층 | 5821397 | 1025 | 1.52388 | 0.0365732 | 1486.71
5821647 | 지상 6층 | 지상 6층 | 5821397 | 1025 | 1.52388 | 0.0365732 | 1486.71
5821658 | 지상 6층 | 지상 6층 | 5821397 | 1025 | 0.935465 | 0.0224512 | 912.649
5821879 | 지상 5층 | 지상 5층 | 5821878 | 225 | 0.205384 | 0.00492921 | 912.816
5821892 | 지상 5층 | 지상 5층 | 5821878 | 225 | 0.42975 | 0.010314 | 1910
5821903 | 지상 5층 | 지상 5층 | 5821878 | 225 | 0.423 | 0.010152 | 1880
5821914 | 지상 5층 | 지상 5층 | 5821878 | 225 | 0.423 | 0.010152 | 1880
5821925 | 지상 5층 | 지상 5층 | 5821878 | 225 | 0.423 | 0.010152 | 1880
5821936 | 지상 5층 | 지상 5층 | 5821878 | 225 | 0.423 | 0.010152 | 1880
5821947 | 지상 5층 | 지상 5층 | 5821878 | 225 | 0.42975 | 0.010314 | 1910
5821958 | 지상 5층 | 지상 5층 | 5821878 | 225 | 0.22725 | 0.005454 | 1010
5821969 | 지상 5층 | 지상 5층 | 5821878 | 225 | 0.49275 | 0.011826 | 2190
5821980 | 지상 5층 | 지상 5층 | 5821878 | 225 | 0.22725 | 0.005454 | 1010
5821991 | 지상 5층 | 지상 5층 | 5821878 | 225 | 0.423 | 0.010152 | 1880
5822002 | 지상 5층 | 지상 5층 | 5821878 | 225 | 0.423 | 0.010152 | 1880
5822013 | 지상 5층 | 지상 5층 | 5821878 | 225 | 0.423 | 0.010152 | 1880
5822024 | 지상 5층 | 지상 5층 | 5821878 | 225 | 0.423 | 0.010152 | 1880
5822035 | 지상 5층 | 지상 5층 | 5821878 | 225 | 0.421875 | 0.010125 | 1875
5822046 | 지상 5층 | 지상 5층 | 5821878 | 225 | 0.22725 | 0.005454 | 1010
5822057 | 지상 5층 | 지상 5층 | 5821878 | 225 | 0.435375 | 0.010449 | 1935
5822068 | 지상 5층 | 지상 5층 | 5821878 | 225 | 0.423 | 0.010152 | 1880
5822079 | 지상 5층 | 지상 5층 | 5821878 | 225 | 0.423 | 0.010152 | 1880
5822090 | 지상 5층 | 지상 5층 | 5821878 | 225 | 0.423 | 0.010152 | 1880
5822101 | 지상 5층 | 지상 5층 | 5821878 | 225 | 0.228375 | 0.005481 | 1015
5822112 | 지상 5층 | 지상 5층 | 5821878 | 225 | 0.200741 | 0.00481779 | 892.184
5821884 | 지상 5층 | 지상 5층 | 5821878 | 550 | 0.502049 | 0.0120492 | 912.816
5821959 | 지상 5층 | 지상 5층 | 5821878 | 550 | 0.5555 | 0.013332 | 1010
5821981 | 지상 5층 | 지상 5층 | 5821878 | 550 | 0.5555 | 0.013332 | 1010
5822047 | 지상 5층 | 지상 5층 | 5821878 | 550 | 0.5555 | 0.013332 | 1010
5822113 | 지상 5층 | 지상 5층 | 5821878 | 550 | 0.490701 | 0.0117768 | 892.184
5821888 | 지상 5층 | 지상 5층 | 5821878 | 1025 | 0.935637 | 0.0224553 | 912.816
5821894 | 지상 5층 | 지상 5층 | 5821878 | 1025 | 1.95775 | 0.046986 | 1910
5821905 | 지상 5층 | 지상 5층 | 5821878 | 1025 | 1.927 | 0.046248 | 1880
5821916 | 지상 5층 | 지상 5층 | 5821878 | 1025 | 1.927 | 0.046248 | 1880
5821927 | 지상 5층 | 지상 5층 | 5821878 | 1025 | 1.927 | 0.046248 | 1880
5821938 | 지상 5층 | 지상 5층 | 5821878 | 1025 | 1.927 | 0.046248 | 1880
5821949 | 지상 5층 | 지상 5층 | 5821878 | 1025 | 1.95775 | 0.046986 | 1910
5821960 | 지상 5층 | 지상 5층 | 5821878 | 1025 | 1.03525 | 0.024846 | 1010
5821971 | 지상 5층 | 지상 5층 | 5821878 | 1025 | 2.24475 | 0.053874 | 2190
5821982 | 지상 5층 | 지상 5층 | 5821878 | 1025 | 1.03525 | 0.024846 | 1010
5821993 | 지상 5층 | 지상 5층 | 5821878 | 1025 | 1.927 | 0.046248 | 1880
5822004 | 지상 5층 | 지상 5층 | 5821878 | 1025 | 1.927 | 0.046248 | 1880
5822015 | 지상 5층 | 지상 5층 | 5821878 | 1025 | 1.927 | 0.046248 | 1880
5822026 | 지상 5층 | 지상 5층 | 5821878 | 1025 | 1.927 | 0.046248 | 1880
5822037 | 지상 5층 | 지상 5층 | 5821878 | 1025 | 1.92187 | 0.046125 | 1875
5822048 | 지상 5층 | 지상 5층 | 5821878 | 1025 | 1.03525 | 0.024846 | 1010
5822059 | 지상 5층 | 지상 5층 | 5821878 | 1025 | 1.98337 | 0.047601 | 1935
5822070 | 지상 5층 | 지상 5층 | 5821878 | 1025 | 1.927 | 0.046248 | 1880
5822081 | 지상 5층 | 지상 5층 | 5821878 | 1025 | 1.927 | 0.046248 | 1880
5822092 | 지상 5층 | 지상 5층 | 5821878 | 1025 | 1.927 | 0.046248 | 1880
5822103 | 지상 5층 | 지상 5층 | 5821878 | 1025 | 1.04038 | 0.024969 | 1015
5822114 | 지상 5층 | 지상 5층 | 5821878 | 1025 | 0.914488 | 0.0219477 | 892.184
5822267 | 지상 5층 | 지상 5층 | 5822266 | 225 | 0.0401388 | 0.000963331 | 178.395
5822283 | 지상 5층 | 지상 5층 | 5822266 | 225 | 0.372825 | 0.0089478 | 1657
5822294 | 지상 5층 | 지상 5층 | 5822266 | 225 | 0.372825 | 0.0089478 | 1657
5822305 | 지상 5층 | 지상 5층 | 5822266 | 225 | 0.372825 | 0.0089478 | 1657
5822316 | 지상 5층 | 지상 5층 | 5822266 | 225 | 0.372825 | 0.0089478 | 1657
5822327 | 지상 5층 | 지상 5층 | 5822266 | 225 | 0.252 | 0.006048 | 1120
5822338 | 지상 5층 | 지상 5층 | 5822266 | 225 | 0.3393 | 0.0081432 | 1508
5822349 | 지상 5층 | 지상 5층 | 5822266 | 225 | 0.3393 | 0.0081432 | 1508
5822360 | 지상 5층 | 지상 5층 | 5822266 | 225 | 0.3393 | 0.0081432 | 1508
5822371 | 지상 5층 | 지상 5층 | 5822266 | 225 | 0.3393 | 0.0081432 | 1508
5822382 | 지상 5층 | 지상 5층 | 5822266 | 225 | 0.252 | 0.006048 | 1120
5822393 | 지상 5층 | 지상 5층 | 5822266 | 225 | 0.333675 | 0.0080082 | 1483
5822404 | 지상 5층 | 지상 5층 | 5822266 | 225 | 0.333675 | 0.0080082 | 1483
5822415 | 지상 5층 | 지상 5층 | 5822266 | 225 | 0.333675 | 0.0080082 | 1483
5822426 | 지상 5층 | 지상 5층 | 5822266 | 225 | 0.333675 | 0.0080082 | 1483
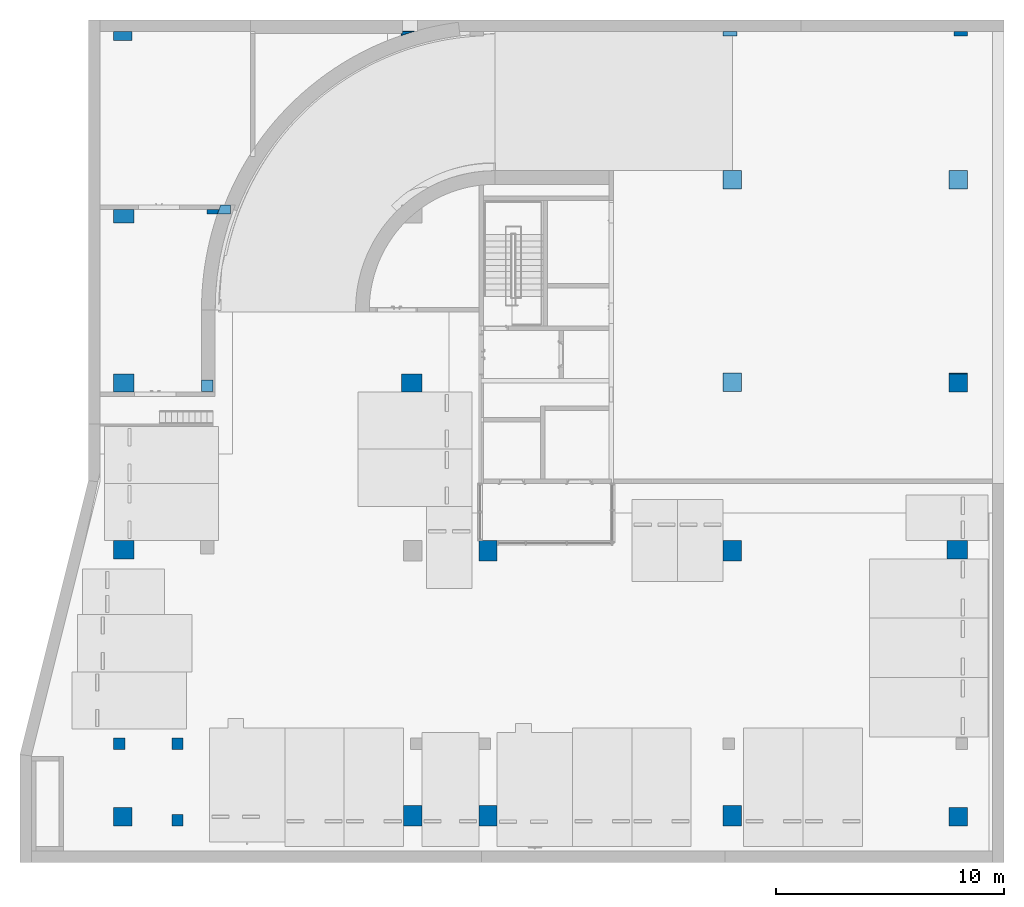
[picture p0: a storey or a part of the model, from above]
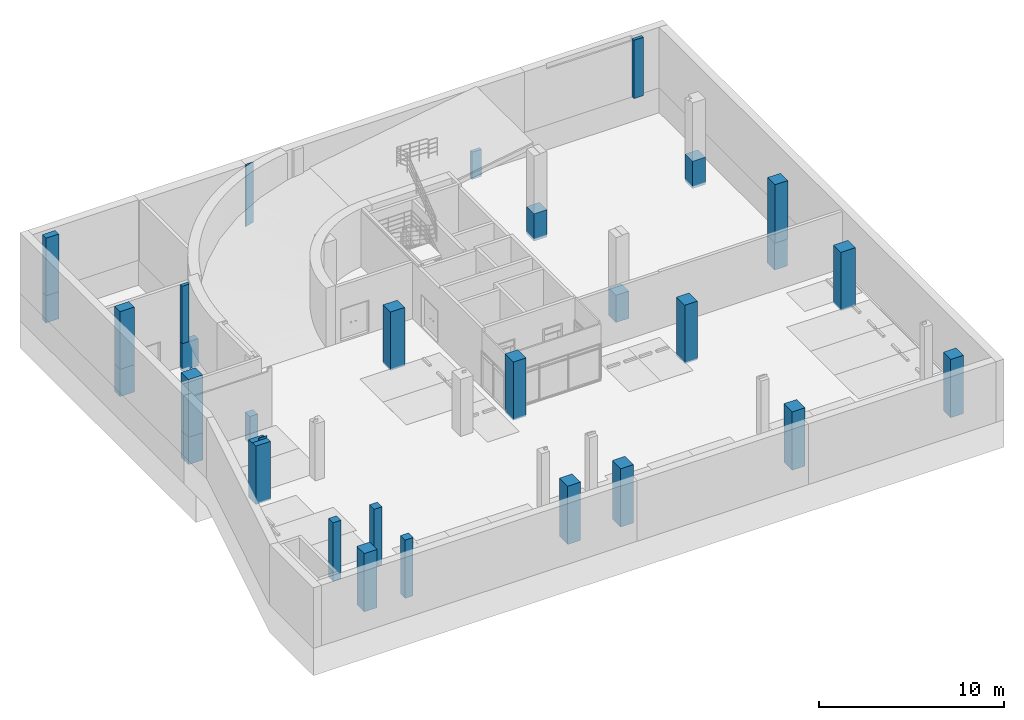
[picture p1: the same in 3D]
Properties of the parts of a building model (IFC2X3), part 31 of 39

# IfcPlate: CW300-THK24.Low-e coating glass:CW300-THK24.Low-e coating glass (2337)
Name (CW300-THK24.Low-e coating glass:CW300-THK24.Low-e coating glass:...) | In | 레벨 | 호스트 ID | 높이 (mm) | 면적 (m2) | 체적 (m3) = NetVolume (m3) | 폭 (mm)
5822437 | 지상 5층 | 지상 5층 | 5822266 | 225 | 0.252 | 0.006048 | 1120
5822448 | 지상 5층 | 지상 5층 | 5822266 | 225 | 0.334511 | 0.00802826 | 1486.71
5822459 | 지상 5층 | 지상 5층 | 5822266 | 225 | 0.334511 | 0.00802826 | 1486.71
5822470 | 지상 5층 | 지상 5층 | 5822266 | 225 | 0.334511 | 0.00802826 | 1486.71
5822481 | 지상 5층 | 지상 5층 | 5822266 | 225 | 0.334511 | 0.00802826 | 1486.71
5822492 | 지상 5층 | 지상 5층 | 5822266 | 225 | 0.334511 | 0.00802826 | 1486.71
5822503 | 지상 5층 | 지상 5층 | 5822266 | 225 | 0.334511 | 0.00802826 | 1486.71
5822514 | 지상 5층 | 지상 5층 | 5822266 | 225 | 0.334511 | 0.00802826 | 1486.71
5822525 | 지상 5층 | 지상 5층 | 5822266 | 225 | 0.205342 | 0.00492821 | 912.631
5822273 | 지상 5층 | 지상 5층 | 5822266 | 550 | 0.098117 | 0.00235481 | 178.395
5822328 | 지상 5층 | 지상 5층 | 5822266 | 550 | 0.616 | 0.014784 | 1120
5822383 | 지상 5층 | 지상 5층 | 5822266 | 550 | 0.616 | 0.014784 | 1120
5822438 | 지상 5층 | 지상 5층 | 5822266 | 550 | 0.616 | 0.014784 | 1120
5822526 | 지상 5층 | 지상 5층 | 5822266 | 550 | 0.501947 | 0.0120467 | 912.631
5822278 | 지상 5층 | 지상 5층 | 5822266 | 1025 | 0.182854 | 0.00438851 | 178.395
5822285 | 지상 5층 | 지상 5층 | 5822266 | 1025 | 1.69842 | 0.0407622 | 1657
5822296 | 지상 5층 | 지상 5층 | 5822266 | 1025 | 1.69842 | 0.0407622 | 1657
5822307 | 지상 5층 | 지상 5층 | 5822266 | 1025 | 1.69842 | 0.0407622 | 1657
5822318 | 지상 5층 | 지상 5층 | 5822266 | 1025 | 1.69842 | 0.0407622 | 1657
5822329 | 지상 5층 | 지상 5층 | 5822266 | 1025 | 1.148 | 0.027552 | 1120
5822340 | 지상 5층 | 지상 5층 | 5822266 | 1025 | 1.5457 | 0.0370968 | 1508
5822351 | 지상 5층 | 지상 5층 | 5822266 | 1025 | 1.5457 | 0.0370968 | 1508
5822362 | 지상 5층 | 지상 5층 | 5822266 | 1025 | 1.5457 | 0.0370968 | 1508
5822373 | 지상 5층 | 지상 5층 | 5822266 | 1025 | 1.5457 | 0.0370968 | 1508
5822384 | 지상 5층 | 지상 5층 | 5822266 | 1025 | 1.148 | 0.027552 | 1120
5822395 | 지상 5층 | 지상 5층 | 5822266 | 1025 | 1.52007 | 0.0364818 | 1483
5822406 | 지상 5층 | 지상 5층 | 5822266 | 1025 | 1.52007 | 0.0364818 | 1483
5822417 | 지상 5층 | 지상 5층 | 5822266 | 1025 | 1.52007 | 0.0364818 | 1483
5822428 | 지상 5층 | 지상 5층 | 5822266 | 1025 | 1.52007 | 0.0364818 | 1483
5822439 | 지상 5층 | 지상 5층 | 5822266 | 1025 | 1.148 | 0.027552 | 1120
5822450 | 지상 5층 | 지상 5층 | 5822266 | 1025 | 1.52388 | 0.0365732 | 1486.71
5822461 | 지상 5층 | 지상 5층 | 5822266 | 1025 | 1.52388 | 0.0365732 | 1486.71
5822472 | 지상 5층 | 지상 5층 | 5822266 | 1025 | 1.52388 | 0.0365732 | 1486.71
5822483 | 지상 5층 | 지상 5층 | 5822266 | 1025 | 1.52388 | 0.0365732 | 1486.71
5822494 | 지상 5층 | 지상 5층 | 5822266 | 1025 | 1.52388 | 0.0365732 | 1486.71
5822505 | 지상 5층 | 지상 5층 | 5822266 | 1025 | 1.52388 | 0.0365732 | 1486.71
5822516 | 지상 5층 | 지상 5층 | 5822266 | 1025 | 1.52388 | 0.0365732 | 1486.71
5822527 | 지상 5층 | 지상 5층 | 5822266 | 1025 | 0.935447 | 0.0224507 | 912.631
5909173 | 지상 2층 | 지상 2층 | 5909172 | 2025 | 1.06312 | 0.025515 | 525
5909192 | 지상 2층 | 지상 2층 | 5909172 | 2025 | 1.053 | 0.025272 | 520
5909179 | 지상 2층 | 지상 2층 | 5909172 | 845 | 0.443625 | 0.010647 | 525
5909185 | 지상 2층 | 지상 2층 | 5909172 | 845 | 1.27172 | 0.0305214 | 1505
5909193 | 지상 2층 | 지상 2층 | 5909172 | 845 | 0.4394 | 0.0105456 | 520
5909203 | 지상 9층 | 지상 9층 | 5909202 | 2075 | 1.08937 | 0.0261448 | 524.996
5909222 | 지상 9층 | 지상 9층 | 5909202 | 2075 | 1.08938 | 0.0261452 | 525.004
5909209 | 지상 9층 | 지상 9층 | 5909202 | 845 | 0.443622 | 0.0106469 | 524.996
5909215 | 지상 9층 | 지상 9층 | 5909202 | 845 | 1.2675 | 0.03042 | 1500
5909223 | 지상 9층 | 지상 9층 | 5909202 | 845 | 0.443628 | 0.0106471 | 525.004
5909233 | 지상 10층 | 지상 10층 | 5909232 | 2075 | 1.08937 | 0.026145 | 525
5909252 | 지상 10층 | 지상 10층 | 5909232 | 2075 | 1.05208 | 0.0252499 | 507.025
5909239 | 지상 10층 | 지상 10층 | 5909232 | 1345 | 0.706125 | 0.016947 | 525
5909245 | 지상 10층 | 지상 10층 | 5909232 | 1345 | 2.0175 | 0.04842 | 1500
5909253 | 지상 10층 | 지상 10층 | 5909232 | 1345 | 0.681949 | 0.0163668 | 507.025
7697251 | 지상 3층 | 지상 3층 | 7697250 | 2075 | 1.69111 | 0.0405866 | 814.991
7697269 | 지상 3층 | 지상 3층 | 7697250 | 2075 | 0.581018 | 0.0139444 | 280.009
7697256 | 지상 3층 | 지상 3층 | 7697250 | 445 | 0.362671 | 0.00870411 | 814.991
7697262 | 지상 3층 | 지상 3층 | 7697250 | 445 | 0.665275 | 0.0159666 | 1495
7697270 | 지상 3층 | 지상 3층 | 7697250 | 445 | 0.124604 | 0.00299049 | 280.009

# IfcPlate: CW410-프로젝트 창:CW410-프로젝트 창 (하부개폐) (939)
Type - PredefinedType: CURTAIN_PANEL; Material: KBIMS-유리, KBIMS-알루미늄
Type - ID 데이터 - 유형 이름: CW410-프로젝트 창 (하부개폐)
Type - 그래픽 - 상부개폐: no; 하부개폐: yes
Type - 기타 - 카테고리: 커튼월 패널; KBIMS-부위코드: E336; 제작정보: bSK-2021_KBIMS2.0-bC; 조달청표준공사코드: ALC1; 패밀리 이름: CW410-프로젝트 창
Type - 재료 및 마감재 - 유리 재료: KBIMS-유리; 프레임 재료: KBIMS-알루미늄
Type - 치수 - 간격띄우기: 80 mm; 유리 두께: 24 mm; 프레임 깊이: 100 mm; 프레임 두께: 50 mm
Type - 해석 특성 - 열 특성 정의 기준: 개략적 유형; 해석 시공: <없음>
Type - Pset_PlateCommon - IsExternal: no
공정 - 생성 공정: 새 구성
기타 - 유형: CW410-프로젝트 창 (하부개폐); 유형 ID: 2126933; 패밀리: CW410-프로젝트 창; 패밀리 및 유형: CW410-프로젝트 창: CW410-프로젝트 창 (하부개폐)
Pset_PlateCommon - Reference: CW410-프로젝트 창 (하부개폐)
Pset_QuantityTakeOff - Reference: CW410-프로젝트 창 (하부개폐)
Name (CW410-프로젝트 창:CW410-프로젝트 창 (하부개폐):...) | In | 레벨 | 호스트 ID | 높이 (mm) | 면적 (m2) | 체적 (m3) = NetVolume (m3) | 폭 (mm)
2880879 | 지상 2층 | 지상 2층 | 2880752 | 550 | 0.605 | 0.0263 | 1100
2895656 | 지상 2층 | 지상 2층 | 2894516 | 550 | 0.497062 | 0.022218 | 903.75
2895657 | 지상 2층 | 지상 2층 | 2894516 | 550 | 0.450313 | 0.02045 | 818.75
2895658 | 지상 2층 | 지상 2층 | 2894516 | 550 | 0.450313 | 0.02045 | 818.75
2895659 | 지상 2층 | 지상 2층 | 2894516 | 550 | 0.450313 | 0.02045 | 818.75
2895660 | 지상 2층 | 지상 2층 | 2894516 | 550 | 0.450313 | 0.02045 | 818.75
2895661 | 지상 2층 | 지상 2층 | 2894516 | 550 | 0.450313 | 0.02045 | 818.75
2895662 | 지상 2층 | 지상 2층 | 2894516 | 550 | 0.450313 | 0.02045 | 818.75
2895663 | 지상 2층 | 지상 2층 | 2894516 | 550 | 0.519063 | 0.02305 | 943.75
2898268 | 지상 2층 | 지상 2층 | 2897084 | 550 | 0.450303 | 0.0204496 | 818.733
2898269 | 지상 2층 | 지상 2층 | 2897084 | 550 | 0.409063 | 0.01889 | 743.75
2898270 | 지상 2층 | 지상 2층 | 2897084 | 550 | 0.409063 | 0.01889 | 743.75
2898271 | 지상 2층 | 지상 2층 | 2897084 | 550 | 0.409063 | 0.01889 | 743.75
2898272 | 지상 2층 | 지상 2층 | 2897084 | 550 | 0.409063 | 0.01889 | 743.75
2898273 | 지상 2층 | 지상 2층 | 2897084 | 550 | 0.409063 | 0.01889 | 743.75
2898274 | 지상 2층 | 지상 2층 | 2897084 | 550 | 0.409063 | 0.01889 | 743.75
2898275 | 지상 2층 | 지상 2층 | 2897084 | 550 | 0.477822 | 0.0214904 | 868.767
2899641 | 지상 2층 | 지상 2층 | 2898536 | 550 | 0.443438 | 0.02019 | 806.25
2899642 | 지상 2층 | 지상 2층 | 2898536 | 550 | 0.402187 | 0.01863 | 731.25
2899643 | 지상 2층 | 지상 2층 | 2898536 | 550 | 0.402187 | 0.01863 | 731.25
2899644 | 지상 2층 | 지상 2층 | 2898536 | 550 | 0.402187 | 0.01863 | 731.25
2899645 | 지상 2층 | 지상 2층 | 2898536 | 550 | 0.402187 | 0.01863 | 731.25
2899646 | 지상 2층 | 지상 2층 | 2898536 | 550 | 0.402187 | 0.01863 | 731.25
2899647 | 지상 2층 | 지상 2층 | 2898536 | 550 | 0.402187 | 0.01863 | 731.25
2899648 | 지상 2층 | 지상 2층 | 2898536 | 550 | 0.470937 | 0.02123 | 856.25
2900959 | 지상 2층 | 지상 2층 | 2900183 | 550 | 0.418314 | 0.0192399 | 760.571
2900960 | 지상 2층 | 지상 2층 | 2900183 | 550 | 0.386964 | 0.0180543 | 703.571
2900961 | 지상 2층 | 지상 2층 | 2900183 | 550 | 0.386964 | 0.0180543 | 703.571
2900962 | 지상 2층 | 지상 2층 | 2900183 | 550 | 0.386964 | 0.0180543 | 703.571
2900963 | 지상 2층 | 지상 2층 | 2900183 | 550 | 0.386964 | 0.0180543 | 703.571
2900964 | 지상 2층 | 지상 2층 | 2900183 | 550 | 0.386964 | 0.0180543 | 703.571
2900965 | 지상 2층 | 지상 2층 | 2900183 | 550 | 0.373214 | 0.0175343 | 678.571
2901886 | 지상 2층 | 지상 2층 | 2901336 | 550 | 0.359792 | 0.0170267 | 654.167
2901887 | 지상 2층 | 지상 2층 | 2901336 | 550 | 0.373542 | 0.0175467 | 679.167
2901888 | 지상 2층 | 지상 2층 | 2901336 | 550 | 0.373542 | 0.0175467 | 679.167
2901889 | 지상 2층 | 지상 2층 | 2901336 | 550 | 0.373542 | 0.0175467 | 679.167
2901890 | 지상 2층 | 지상 2층 | 2901336 | 550 | 0.373542 | 0.0175467 | 679.167
2901891 | 지상 2층 | 지상 2층 | 2901336 | 550 | 0.331052 | 0.0159398 | 601.913
2903215 | 지상 2층 | 지상 2층 | 2902261 | 550 | 0.592364 | 0.0258221 | 1077.03
2903216 | 지상 2층 | 지상 2층 | 2902261 | 550 | 0.561 | 0.024636 | 1020
2903217 | 지상 2층 | 지상 2층 | 2902261 | 550 | 0.561 | 0.024636 | 1020
2903218 | 지상 2층 | 지상 2층 | 2902261 | 550 | 0.561 | 0.024636 | 1020
2903219 | 지상 2층 | 지상 2층 | 2902261 | 550 | 0.54725 | 0.024116 | 995
2904561 | 지상 2층 | 지상 2층 | 2903630 | 550 | 0.54725 | 0.024116 | 995
2904562 | 지상 2층 | 지상 2층 | 2903630 | 550 | 0.561 | 0.024636 | 1020
2904563 | 지상 2층 | 지상 2층 | 2903630 | 550 | 0.561 | 0.024636 | 1020
2904564 | 지상 2층 | 지상 2층 | 2903630 | 550 | 0.561 | 0.024636 | 1020
2904565 | 지상 2층 | 지상 2층 | 2903630 | 550 | 0.602313 | 0.0261984 | 1095.11
2907079 | 지상 2층 | 지상 2층 | 2904974 | 550 | 0.646177 | 0.0278572 | 1174.87
2907080 | 지상 2층 | 지상 2층 | 2904974 | 550 | 0.646323 | 0.0278628 | 1175.13
2907825 | 지상 2층 | 지상 2층 | 2905064 | 550 | 0.605559 | 0.0263211 | 1101.02
2907826 | 지상 2층 | 지상 2층 | 2905064 | 550 | 0.574063 | 0.02513 | 1043.75
2907827 | 지상 2층 | 지상 2층 | 2905064 | 550 | 0.574063 | 0.02513 | 1043.75
2907828 | 지상 2층 | 지상 2층 | 2905064 | 550 | 0.560313 | 0.02461 | 1018.75
2908496 | 지상 2층 | 지상 2층 | 2905217 | 550 | 0.560313 | 0.02461 | 1018.75
2908497 | 지상 2층 | 지상 2층 | 2905217 | 550 | 0.574063 | 0.02513 | 1043.75
2908690 | 지상 2층 | 지상 2층 | 2905217 | 550 | 0.574063 | 0.02513 | 1043.75
2908762 | 지상 2층 | 지상 2층 | 2905217 | 550 | 0.601466 | 0.0261664 | 1093.57
2909472 | 지상 2층 | 지상 2층 | 2905351 | 550 | 0.543729 | 0.0239829 | 988.599
2909473 | 지상 2층 | 지상 2층 | 2905351 | 550 | 0.515625 | 0.02292 | 937.5
2909554 | 지상 2층 | 지상 2층 | 2905351 | 550 | 0.515625 | 0.02292 | 937.5
2909654 | 지상 2층 | 지상 2층 | 2905351 | 550 | 0.501875 | 0.0224 | 912.5
2910076 | 지상 2층 | 지상 2층 | 2905462 | 550 | 0.501875 | 0.0224 | 912.5
2910077 | 지상 2층 | 지상 2층 | 2905462 | 550 | 0.515625 | 0.02292 | 937.5
2910172 | 지상 2층 | 지상 2층 | 2905462 | 550 | 0.515625 | 0.02292 | 937.5
2910258 | 지상 2층 | 지상 2층 | 2905462 | 550 | 0.550912 | 0.0242545 | 1001.66
2911569 | 지상 2층 | 지상 2층 | 2905548 | 550 | 0.446142 | 0.0202923 | 811.167
2911570 | 지상 2층 | 지상 2층 | 2905548 | 550 | 0.414792 | 0.0191067 | 754.167
2911571 | 지상 2층 | 지상 2층 | 2905548 | 550 | 0.414792 | 0.0191067 | 754.167
2911572 | 지상 2층 | 지상 2층 | 2905548 | 550 | 0.414792 | 0.0191067 | 754.167
2911573 | 지상 2층 | 지상 2층 | 2905548 | 550 | 0.414792 | 0.0191067 | 754.167
2911574 | 지상 2층 | 지상 2층 | 2905548 | 550 | 0.401042 | 0.0185867 | 729.167
2912534 | 지상 2층 | 지상 2층 | 2905633 | 550 | 0.401042 | 0.0185867 | 729.167
2912535 | 지상 2층 | 지상 2층 | 2905633 | 550 | 0.414792 | 0.0191067 | 754.167
2912536 | 지상 2층 | 지상 2층 | 2905633 | 550 | 0.414792 | 0.0191067 | 754.167
2912537 | 지상 2층 | 지상 2층 | 2905633 | 550 | 0.414792 | 0.0191067 | 754.167
2912538 | 지상 2층 | 지상 2층 | 2905633 | 550 | 0.414792 | 0.0191067 | 754.167
2912539 | 지상 2층 | 지상 2층 | 2905633 | 550 | 0.446142 | 0.0202923 | 811.167
2913307 | 지상 2층 | 지상 2층 | 2905747 | 550 | 0.461037 | 0.0208556 | 838.25
2913308 | 지상 2층 | 지상 2층 | 2905747 | 550 | 0.402187 | 0.01863 | 731.25
2913309 | 지상 2층 | 지상 2층 | 2905747 | 550 | 0.402187 | 0.01863 | 731.25
2913310 | 지상 2층 | 지상 2층 | 2905747 | 550 | 0.402187 | 0.01863 | 731.25
2913311 | 지상 2층 | 지상 2층 | 2905747 | 550 | 0.402187 | 0.01863 | 731.25
2913312 | 지상 2층 | 지상 2층 | 2905747 | 550 | 0.402187 | 0.01863 | 731.25
2913388 | 지상 2층 | 지상 2층 | 2905747 | 550 | 0.402187 | 0.01863 | 731.25
2913488 | 지상 2층 | 지상 2층 | 2905747 | 550 | 0.443438 | 0.02019 | 806.25
2914531 | 지상 2층 | 지상 2층 | 2905902 | 550 | 0.473 | 0.021308 | 860
2914532 | 지상 2층 | 지상 2층 | 2905902 | 550 | 0.40425 | 0.018708 | 735
2914533 | 지상 2층 | 지상 2층 | 2905902 | 550 | 0.40425 | 0.018708 | 735
2914534 | 지상 2층 | 지상 2층 | 2905902 | 550 | 0.40425 | 0.018708 | 735
2914535 | 지상 2층 | 지상 2층 | 2905902 | 550 | 0.40425 | 0.018708 | 735
2914536 | 지상 2층 | 지상 2층 | 2905902 | 550 | 0.40425 | 0.018708 | 735
2914537 | 지상 2층 | 지상 2층 | 2905902 | 550 | 0.40425 | 0.018708 | 735
2914538 | 지상 2층 | 지상 2층 | 2905902 | 550 | 0.40425 | 0.018708 | 735
2914539 | 지상 2층 | 지상 2층 | 2905902 | 550 | 0.40425 | 0.018708 | 735
2914540 | 지상 2층 | 지상 2층 | 2905902 | 550 | 0.4455 | 0.020268 | 810
2915929 | 지상 2층 | 지상 2층 | 2914928 | 550 | 0.541378 | 0.0238939 | 984.323
2915930 | 지상 2층 | 지상 2층 | 2914928 | 550 | 0.516389 | 0.0229489 | 938.889
2915931 | 지상 2층 | 지상 2층 | 2914928 | 550 | 0.516389 | 0.0229489 | 938.889
2915932 | 지상 2층 | 지상 2층 | 2914928 | 550 | 0.516389 | 0.0229489 | 938.889
2915933 | 지상 2층 | 지상 2층 | 2914928 | 550 | 0.516389 | 0.0229489 | 938.889
2915934 | 지상 2층 | 지상 2층 | 2914928 | 550 | 0.516389 | 0.0229489 | 938.889
2915935 | 지상 2층 | 지상 2층 | 2914928 | 550 | 0.516389 | 0.0229489 | 938.889
2915936 | 지상 2층 | 지상 2층 | 2914928 | 550 | 0.516389 | 0.0229489 | 938.889
2915937 | 지상 2층 | 지상 2층 | 2914928 | 550 | 0.502639 | 0.0224289 | 913.889
2926343 | 지상 3층 | 지상 3층 | 2926331 | 450 | 0.393608 | 0.0187542 | 874.684
2929640 | 지상 3층 | 지상 3층 | 2927264 | 550 | 0.4917 | 0.0220152 | 894
2929784 | 지상 3층 | 지상 3층 | 2927264 | 550 | 0.4422 | 0.0201432 | 804
2930134 | 지상 3층 | 지상 3층 | 2927264 | 550 | 0.4422 | 0.0201432 | 804
2930222 | 지상 3층 | 지상 3층 | 2927264 | 550 | 0.4422 | 0.0201432 | 804
2930310 | 지상 3층 | 지상 3층 | 2927264 | 550 | 0.4422 | 0.0201432 | 804
2930392 | 지상 3층 | 지상 3층 | 2927264 | 550 | 0.4422 | 0.0201432 | 804
2930474 | 지상 3층 | 지상 3층 | 2927264 | 550 | 0.4422 | 0.0201432 | 804
2930518 | 지상 3층 | 지상 3층 | 2927264 | 550 | 0.4752 | 0.0213912 | 864
2930632 | 지상 3층 | 지상 3층 | 2927264 | 550 | 0.43395 | 0.0198312 | 789
2930670 | 지상 3층 | 지상 3층 | 2927264 | 550 | 0.40095 | 0.0185832 | 729
2930708 | 지상 3층 | 지상 3층 | 2927264 | 550 | 0.40095 | 0.0185832 | 729
2930790 | 지상 3층 | 지상 3층 | 2927264 | 550 | 0.40095 | 0.0185832 | 729
2930828 | 지상 3층 | 지상 3층 | 2927264 | 550 | 0.40095 | 0.0185832 | 729
2930866 | 지상 3층 | 지상 3층 | 2927264 | 550 | 0.40095 | 0.0185832 | 729
2930904 | 지상 3층 | 지상 3층 | 2927264 | 550 | 0.40095 | 0.0185832 | 729
2930942 | 지상 3층 | 지상 3층 | 2927264 | 550 | 0.43395 | 0.0198312 | 789
2931108 | 지상 3층 | 지상 3층 | 2927264 | 550 | 0.4268 | 0.0195608 | 776
2931065 | 지상 3층 | 지상 3층 | 2927264 | 550 | 0.3938 | 0.0183128 | 716
2931143 | 지상 3층 | 지상 3층 | 2927264 | 550 | 0.3938 | 0.0183128 | 716
2934162 | 지상 3층 | 지상 3층 | 2927264 | 550 | 0.3938 | 0.0183128 | 716
2934127 | 지상 3층 | 지상 3층 | 2927264 | 550 | 0.3938 | 0.0183128 | 716
2931181 | 지상 3층 | 지상 3층 | 2927264 | 550 | 0.3938 | 0.0183128 | 716
2931257 | 지상 3층 | 지상 3층 | 2927264 | 550 | 0.3938 | 0.0183128 | 716
2931298 | 지상 3층 | 지상 3층 | 2927264 | 550 | 0.4268 | 0.0195608 | 776
2931377 | 지상 3층 | 지상 3층 | 2927264 | 550 | 0.4323 | 0.0197688 | 786
2931415 | 지상 3층 | 지상 3층 | 2927264 | 550 | 0.3938 | 0.0183128 | 716
2933433 | 지상 3층 | 지상 3층 | 2927264 | 550 | 0.3938 | 0.0183128 | 716
2933400 | 지상 3층 | 지상 3층 | 2927264 | 550 | 0.3938 | 0.0183128 | 716
2933365 | 지상 3층 | 지상 3층 | 2927264 | 550 | 0.3938 | 0.0183128 | 716
2933330 | 지상 3층 | 지상 3층 | 2927264 | 550 | 0.3938 | 0.0183128 | 716
2933295 | 지상 3층 | 지상 3층 | 2927264 | 550 | 0.3938 | 0.0183128 | 716
2933262 | 지상 3층 | 지상 3층 | 2927264 | 550 | 0.3938 | 0.0183128 | 716
2933227 | 지상 3층 | 지상 3층 | 2927264 | 550 | 0.3938 | 0.0183128 | 716
2933192 | 지상 3층 | 지상 3층 | 2927264 | 550 | 0.3938 | 0.0183128 | 716
2933159 | 지상 3층 | 지상 3층 | 2927264 | 550 | 0.3938 | 0.0183128 | 716
2931491 | 지상 3층 | 지상 3층 | 2927264 | 550 | 0.3938 | 0.0183128 | 716
2931529 | 지상 3층 | 지상 3층 | 2927264 | 550 | 0.3531 | 0.0167736 | 642
2931567 | 지상 3층 | 지상 3층 | 2927264 | 550 | 0.40315 | 0.0186664 | 733
2936736 | 지상 4층 | 지상 4층 | 2936724 | 550 | 0.432517 | 0.019777 | 786.395
3184190 | 지상 4층 | 지상 4층 | 2936724 | 550 | 0.3938 | 0.0183128 | 716
3184139 | 지상 4층 | 지상 4층 | 2936724 | 550 | 0.3938 | 0.0183128 | 716
3184056 | 지상 4층 | 지상 4층 | 2936724 | 550 | 0.3938 | 0.0183128 | 716
3184001 | 지상 4층 | 지상 4층 | 2936724 | 550 | 0.3938 | 0.0183128 | 716
3183950 | 지상 4층 | 지상 4층 | 2936724 | 550 | 0.3938 | 0.0183128 | 716
2937120 | 지상 4층 | 지상 4층 | 2936724 | 550 | 0.3938 | 0.0183128 | 716
2937109 | 지상 4층 | 지상 4층 | 2936724 | 550 | 0.3938 | 0.0183128 | 716
2937098 | 지상 4층 | 지상 4층 | 2936724 | 550 | 0.3938 | 0.0183128 | 716
2937087 | 지상 4층 | 지상 4층 | 2936724 | 550 | 0.3938 | 0.0183128 | 716
2937076 | 지상 4층 | 지상 4층 | 2936724 | 550 | 0.3938 | 0.0183128 | 716
2937025 | 지상 4층 | 지상 4층 | 2936724 | 550 | 0.3938 | 0.0183128 | 716
2937036 | 지상 4층 | 지상 4층 | 2936724 | 550 | 0.3531 | 0.0167736 | 642
2937047 | 지상 4층 | 지상 4층 | 2936724 | 550 | 0.40315 | 0.0186664 | 733
2938163 | 지상 4층 | 지상 4층 | 2938145 | 550 | 0.441925 | 0.0201328 | 803.5
2938174 | 지상 4층 | 지상 4층 | 2938145 | 550 | 0.441925 | 0.0201328 | 803.5
2938186 | 지상 4층 | 지상 4층 | 2938145 | 550 | 0.441925 | 0.0201328 | 803.5
2938193 | 지상 4층 | 지상 4층 | 2938145 | 550 | 0.441925 | 0.0201328 | 803.5
2938200 | 지상 4층 | 지상 4층 | 2938145 | 550 | 0.441925 | 0.0201328 | 803.5
2938211 | 지상 4층 | 지상 4층 | 2938145 | 550 | 0.441925 | 0.0201328 | 803.5
2938222 | 지상 4층 | 지상 4층 | 2938145 | 550 | 0.441925 | 0.0201328 | 803.5
2938233 | 지상 4층 | 지상 4층 | 2938145 | 550 | 0.441925 | 0.0201328 | 803.5
2938255 | 지상 4층 | 지상 4층 | 2938145 | 550 | 0.40095 | 0.0185832 | 729
2938266 | 지상 4층 | 지상 4층 | 2938145 | 550 | 0.40095 | 0.0185832 | 729
2938277 | 지상 4층 | 지상 4층 | 2938145 | 550 | 0.40095 | 0.0185832 | 729
2938288 | 지상 4층 | 지상 4층 | 2938145 | 550 | 0.40095 | 0.0185832 | 729
2938299 | 지상 4층 | 지상 4층 | 2938145 | 550 | 0.40095 | 0.0185832 | 729
2938310 | 지상 4층 | 지상 4층 | 2938145 | 550 | 0.40095 | 0.0185832 | 729
2938321 | 지상 4층 | 지상 4층 | 2938145 | 550 | 0.40095 | 0.0185832 | 729
2938332 | 지상 4층 | 지상 4층 | 2938145 | 550 | 0.40095 | 0.0185832 | 729
2938365 | 지상 4층 | 지상 4층 | 2938145 | 550 | 0.394075 | 0.0183232 | 716.5
2938354 | 지상 4층 | 지상 4층 | 2938145 | 550 | 0.394075 | 0.0183232 | 716.5
2938376 | 지상 4층 | 지상 4층 | 2938145 | 550 | 0.394075 | 0.0183232 | 716.5
2938603 | 지상 4층 | 지상 4층 | 2938145 | 550 | 0.394075 | 0.0183232 | 716.5
2938592 | 지상 4층 | 지상 4층 | 2938145 | 550 | 0.394075 | 0.0183232 | 716.5
2938387 | 지상 4층 | 지상 4층 | 2938145 | 550 | 0.394075 | 0.0183232 | 716.5
2938402 | 지상 4층 | 지상 4층 | 2938145 | 550 | 0.394075 | 0.0183232 | 716.5
2938413 | 지상 4층 | 지상 4층 | 2938145 | 550 | 0.394075 | 0.0183232 | 716.5
2941463 | 지상 3층 | 지상 3층 | 2940510 | 550 | 0.51975 | 0.023076 | 945
2941768 | 지상 3층 | 지상 3층 | 2940510 | 550 | 0.50325 | 0.022452 | 915
2941815 | 지상 3층 | 지상 3층 | 2940510 | 550 | 0.50325 | 0.022452 | 915
2941940 | 지상 3층 | 지상 3층 | 2940510 | 550 | 0.50325 | 0.022452 | 915
2941985 | 지상 3층 | 지상 3층 | 2940510 | 550 | 0.50325 | 0.022452 | 915
2942030 | 지상 3층 | 지상 3층 | 2940510 | 550 | 0.50325 | 0.022452 | 915
2942075 | 지상 3층 | 지상 3층 | 2940510 | 550 | 0.50325 | 0.022452 | 915
2942120 | 지상 3층 | 지상 3층 | 2940510 | 550 | 0.50325 | 0.022452 | 915
2942163 | 지상 3층 | 지상 3층 | 2940510 | 550 | 0.50325 | 0.022452 | 915
2942331 | 지상 3층 | 지상 3층 | 2940510 | 550 | 0.50325 | 0.022452 | 915
2942376 | 지상 3층 | 지상 3층 | 2940510 | 550 | 0.50325 | 0.022452 | 915
2942655 | 지상 3층 | 지상 3층 | 2940510 | 550 | 0.51975 | 0.023076 | 945
2942969 | 지상 3층 | 지상 3층 | 2940510 | 550 | 0.5885 | 0.025676 | 1070
2942973 | 지상 3층 | 지상 3층 | 2940510 | 550 | 0.5885 | 0.025676 | 1070
2942981 | 지상 3층 | 지상 3층 | 2940510 | 550 | 0.50325 | 0.022452 | 915
2942985 | 지상 3층 | 지상 3층 | 2940510 | 550 | 0.50325 | 0.022452 | 915
2942989 | 지상 3층 | 지상 3층 | 2940510 | 550 | 0.50325 | 0.022452 | 915
2942993 | 지상 3층 | 지상 3층 | 2940510 | 550 | 0.50325 | 0.022452 | 915
2942997 | 지상 3층 | 지상 3층 | 2940510 | 550 | 0.50325 | 0.022452 | 915
2943001 | 지상 3층 | 지상 3층 | 2940510 | 550 | 0.50325 | 0.022452 | 915
2943005 | 지상 3층 | 지상 3층 | 2940510 | 550 | 0.50325 | 0.022452 | 915
2943009 | 지상 3층 | 지상 3층 | 2940510 | 550 | 0.50325 | 0.022452 | 915
2943013 | 지상 3층 | 지상 3층 | 2940510 | 550 | 0.50325 | 0.022452 | 915
2943017 | 지상 3층 | 지상 3층 | 2940510 | 550 | 0.5005 | 0.022348 | 910
2943197 | 지상 3층 | 지상 3층 | 2940510 | 550 | 0.5335 | 0.023596 | 970
2943201 | 지상 3층 | 지상 3층 | 2940510 | 550 | 0.50325 | 0.022452 | 915
2943205 | 지상 3층 | 지상 3층 | 2940510 | 550 | 0.50325 | 0.022452 | 915
2943209 | 지상 3층 | 지상 3층 | 2940510 | 550 | 0.50325 | 0.022452 | 915
2943213 | 지상 3층 | 지상 3층 | 2940510 | 550 | 0.50325 | 0.022452 | 915
2943217 | 지상 3층 | 지상 3층 | 2940510 | 550 | 0.50325 | 0.022452 | 915
2943221 | 지상 3층 | 지상 3층 | 2940510 | 550 | 0.50325 | 0.022452 | 915
2943225 | 지상 3층 | 지상 3층 | 2940510 | 550 | 0.50325 | 0.022452 | 915
2943229 | 지상 3층 | 지상 3층 | 2940510 | 550 | 0.55825 | 0.024532 | 1015
2944613 | 지상 4층 | 지상 4층 | 2944600 | 550 | 0.51975 | 0.023076 | 945
2944637 | 지상 4층 | 지상 4층 | 2944600 | 550 | 0.50325 | 0.022452 | 915
2944651 | 지상 4층 | 지상 4층 | 2944600 | 550 | 0.50325 | 0.022452 | 915
2944665 | 지상 4층 | 지상 4층 | 2944600 | 550 | 0.50325 | 0.022452 | 915
2944679 | 지상 4층 | 지상 4층 | 2944600 | 550 | 0.50325 | 0.022452 | 915
2944693 | 지상 4층 | 지상 4층 | 2944600 | 550 | 0.50325 | 0.022452 | 915
2944707 | 지상 4층 | 지상 4층 | 2944600 | 550 | 0.50325 | 0.022452 | 915
2944721 | 지상 4층 | 지상 4층 | 2944600 | 550 | 0.50325 | 0.022452 | 915
2944735 | 지상 4층 | 지상 4층 | 2944600 | 550 | 0.50325 | 0.022452 | 915
2944749 | 지상 4층 | 지상 4층 | 2944600 | 550 | 0.50325 | 0.022452 | 915
2944763 | 지상 4층 | 지상 4층 | 2944600 | 550 | 0.50325 | 0.022452 | 915
2944777 | 지상 4층 | 지상 4층 | 2944600 | 550 | 0.51975 | 0.023076 | 945
2944817 | 지상 4층 | 지상 4층 | 2944600 | 550 | 0.5885 | 0.025676 | 1070
2944821 | 지상 4층 | 지상 4층 | 2944600 | 550 | 0.5885 | 0.025676 | 1070
2944829 | 지상 4층 | 지상 4층 | 2944600 | 550 | 0.50325 | 0.022452 | 915
2944833 | 지상 4층 | 지상 4층 | 2944600 | 550 | 0.50325 | 0.022452 | 915
2944837 | 지상 4층 | 지상 4층 | 2944600 | 550 | 0.50325 | 0.022452 | 915
2944841 | 지상 4층 | 지상 4층 | 2944600 | 550 | 0.50325 | 0.022452 | 915
2944845 | 지상 4층 | 지상 4층 | 2944600 | 550 | 0.50325 | 0.022452 | 915
2944849 | 지상 4층 | 지상 4층 | 2944600 | 550 | 0.50325 | 0.022452 | 915
2944853 | 지상 4층 | 지상 4층 | 2944600 | 550 | 0.50325 | 0.022452 | 915
2944857 | 지상 4층 | 지상 4층 | 2944600 | 550 | 0.50325 | 0.022452 | 915
2944861 | 지상 4층 | 지상 4층 | 2944600 | 550 | 0.50325 | 0.022452 | 915
2944865 | 지상 4층 | 지상 4층 | 2944600 | 550 | 0.5005 | 0.022348 | 910
2944996 | 지상 4층 | 지상 4층 | 2944600 | 550 | 0.5335 | 0.023596 | 970
2945000 | 지상 4층 | 지상 4층 | 2944600 | 550 | 0.50325 | 0.022452 | 915
2945004 | 지상 4층 | 지상 4층 | 2944600 | 550 | 0.50325 | 0.022452 | 915
2945008 | 지상 4층 | 지상 4층 | 2944600 | 550 | 0.50325 | 0.022452 | 915
2945012 | 지상 4층 | 지상 4층 | 2944600 | 550 | 0.50325 | 0.022452 | 915
2945016 | 지상 4층 | 지상 4층 | 2944600 | 550 | 0.50325 | 0.022452 | 915
2945020 | 지상 4층 | 지상 4층 | 2944600 | 550 | 0.50325 | 0.022452 | 915
2945024 | 지상 4층 | 지상 4층 | 2944600 | 550 | 0.50325 | 0.022452 | 915
2945028 | 지상 4층 | 지상 4층 | 2944600 | 550 | 0.55825 | 0.024532 | 1015
2945787 | 지상 3층 | 지상 3층 | 2945775 | 550 | 0.430867 | 0.0197146 | 783.395
2945874 | 지상 3층 | 지상 3층 | 2945775 | 550 | 0.385 | 0.01798 | 700
2945885 | 지상 3층 | 지상 3층 | 2945775 | 550 | 0.40095 | 0.0185832 | 729
2947768 | 지상 3층 | 지상 3층 | 2945775 | 550 | 0.40095 | 0.0185832 | 729
2945896 | 지상 3층 | 지상 3층 | 2945775 | 550 | 0.40095 | 0.0185832 | 729
2945907 | 지상 3층 | 지상 3층 | 2945775 | 550 | 0.40095 | 0.0185832 | 729
2945918 | 지상 3층 | 지상 3층 | 2945775 | 550 | 0.40095 | 0.0185832 | 729
2945929 | 지상 3층 | 지상 3층 | 2945775 | 550 | 0.40095 | 0.0185832 | 729
2945940 | 지상 3층 | 지상 3층 | 2945775 | 550 | 0.40095 | 0.0185832 | 729
2945951 | 지상 3층 | 지상 3층 | 2945775 | 550 | 0.43395 | 0.0198312 | 789
2945995 | 지상 3층 | 지상 3층 | 2945775 | 550 | 0.4268 | 0.0195608 | 776
2947250 | 지상 3층 | 지상 3층 | 2945775 | 550 | 0.3938 | 0.0183128 | 716
2945984 | 지상 3층 | 지상 3층 | 2945775 | 550 | 0.3938 | 0.0183128 | 716
2946006 | 지상 3층 | 지상 3층 | 2945775 | 550 | 0.3938 | 0.0183128 | 716
2946233 | 지상 3층 | 지상 3층 | 2945775 | 550 | 0.3938 | 0.0183128 | 716
2946222 | 지상 3층 | 지상 3층 | 2945775 | 550 | 0.3938 | 0.0183128 | 716
2946017 | 지상 3층 | 지상 3층 | 2945775 | 550 | 0.3938 | 0.0183128 | 716
2946032 | 지상 3층 | 지상 3층 | 2945775 | 550 | 0.4268 | 0.0195608 | 776
2946054 | 지상 3층 | 지상 3층 | 2945775 | 550 | 0.4268 | 0.0195608 | 776
2946692 | 지상 3층 | 지상 3층 | 2945775 | 550 | 0.3938 | 0.0183128 | 716
2946653 | 지상 3층 | 지상 3층 | 2945775 | 550 | 0.3938 | 0.0183128 | 716
2946065 | 지상 3층 | 지상 3층 | 2945775 | 550 | 0.3938 | 0.0183128 | 716
2946211 | 지상 3층 | 지상 3층 | 2945775 | 550 | 0.3938 | 0.0183128 | 716
2946200 | 지상 3층 | 지상 3층 | 2945775 | 550 | 0.3938 | 0.0183128 | 716
2946189 | 지상 3층 | 지상 3층 | 2945775 | 550 | 0.3938 | 0.0183128 | 716
2946182 | 지상 3층 | 지상 3층 | 2945775 | 550 | 0.3938 | 0.0183128 | 716
2946171 | 지상 3층 | 지상 3층 | 2945775 | 550 | 0.3938 | 0.0183128 | 716
2946160 | 지상 3층 | 지상 3층 | 2945775 | 550 | 0.3938 | 0.0183128 | 716
2946149 | 지상 3층 | 지상 3층 | 2945775 | 550 | 0.3938 | 0.0183128 | 716
2946076 | 지상 3층 | 지상 3층 | 2945775 | 550 | 0.3938 | 0.0183128 | 716
2946087 | 지상 3층 | 지상 3층 | 2945775 | 550 | 0.3531 | 0.0167736 | 642
2946098 | 지상 3층 | 지상 3층 | 2945775 | 550 | 0.3861 | 0.0180216 | 702
2948727 | 지상 4층 | 지상 4층 | 2948716 | 550 | 0.452317 | 0.0205258 | 822.395
3189850 | 지상 4층 | 지상 4층 | 2948716 | 550 | 0.3938 | 0.0183128 | 716
3189793 | 지상 4층 | 지상 4층 | 2948716 | 550 | 0.3938 | 0.0183128 | 716
3189731 | 지상 4층 | 지상 4층 | 2948716 | 550 | 0.3938 | 0.0183128 | 716
2949018 | 지상 4층 | 지상 4층 | 2948716 | 550 | 0.3938 | 0.0183128 | 716
2949007 | 지상 4층 | 지상 4층 | 2948716 | 550 | 0.3938 | 0.0183128 | 716
2948996 | 지상 4층 | 지상 4층 | 2948716 | 550 | 0.3938 | 0.0183128 | 716
2948989 | 지상 4층 | 지상 4층 | 2948716 | 550 | 0.3938 | 0.0183128 | 716
2948978 | 지상 4층 | 지상 4층 | 2948716 | 550 | 0.3938 | 0.0183128 | 716
2948967 | 지상 4층 | 지상 4층 | 2948716 | 550 | 0.3938 | 0.0183128 | 716
2948956 | 지상 4층 | 지상 4층 | 2948716 | 550 | 0.3938 | 0.0183128 | 716
2948912 | 지상 4층 | 지상 4층 | 2948716 | 550 | 0.3938 | 0.0183128 | 716
2948923 | 지상 4층 | 지상 4층 | 2948716 | 550 | 0.3531 | 0.0167736 | 642
2948934 | 지상 4층 | 지상 4층 | 2948716 | 550 | 0.3861 | 0.0180216 | 702
2949942 | 지상 4층 | 지상 4층 | 2949931 | 550 | 0.462275 | 0.0209024 | 840.5
2949947 | 지상 4층 | 지상 4층 | 2949931 | 550 | 0.385 | 0.01798 | 700
2949958 | 지상 4층 | 지상 4층 | 2949931 | 550 | 0.40095 | 0.0185832 | 729
2950312 | 지상 4층 | 지상 4층 | 2949931 | 550 | 0.40095 | 0.0185832 | 729
2949969 | 지상 4층 | 지상 4층 | 2949931 | 550 | 0.40095 | 0.0185832 | 729
2949980 | 지상 4층 | 지상 4층 | 2949931 | 550 | 0.40095 | 0.0185832 | 729
2949991 | 지상 4층 | 지상 4층 | 2949931 | 550 | 0.40095 | 0.0185832 | 729
2950002 | 지상 4층 | 지상 4층 | 2949931 | 550 | 0.40095 | 0.0185832 | 729
2950013 | 지상 4층 | 지상 4층 | 2949931 | 550 | 0.40095 | 0.0185832 | 729
2950024 | 지상 4층 | 지상 4층 | 2949931 | 550 | 0.43395 | 0.0198312 | 789
2950057 | 지상 4층 | 지상 4층 | 2949931 | 550 | 0.4268 | 0.0195608 | 776
2950301 | 지상 4층 | 지상 4층 | 2949931 | 550 | 0.3938 | 0.0183128 | 716
2950046 | 지상 4층 | 지상 4층 | 2949931 | 550 | 0.3938 | 0.0183128 | 716
2950068 | 지상 4층 | 지상 4층 | 2949931 | 550 | 0.3938 | 0.0183128 | 716
2950255 | 지상 4층 | 지상 4층 | 2949931 | 550 | 0.3938 | 0.0183128 | 716
2950244 | 지상 4층 | 지상 4층 | 2949931 | 550 | 0.3938 | 0.0183128 | 716
2950079 | 지상 4층 | 지상 4층 | 2949931 | 550 | 0.3938 | 0.0183128 | 716
2950094 | 지상 4층 | 지상 4층 | 2949931 | 550 | 0.482625 | 0.021672 | 877.5
2951917 | 지상 3층 | 지상 3층 | 2951075 | 550 | 0.591809 | 0.0258011 | 1076.02
2952519 | 지상 3층 | 지상 3층 | 2951075 | 550 | 0.5115 | 0.022764 | 929.999
2952699 | 지상 3층 | 지상 3층 | 2951075 | 550 | 0.5115 | 0.022764 | 929.999
2952787 | 지상 3층 | 지상 3층 | 2951075 | 550 | 0.5115 | 0.022764 | 929.999
2952825 | 지상 3층 | 지상 3층 | 2951075 | 550 | 0.5115 | 0.022764 | 929.999
2952863 | 지상 3층 | 지상 3층 | 2951075 | 550 | 0.5115 | 0.022764 | 929.999
2952901 | 지상 3층 | 지상 3층 | 2951075 | 550 | 0.5115 | 0.022764 | 929.999
2952939 | 지상 3층 | 지상 3층 | 2951075 | 550 | 0.5115 | 0.022764 | 929.999
2953116 | 지상 3층 | 지상 3층 | 2951075 | 550 | 0.49775 | 0.022244 | 904.999
2960464 | 지상 10층 | 지상 10층 | 2960446 | 550 | 0.441925 | 0.0201328 | 803.5
2960717 | 지상 10층 | 지상 10층 | 2960446 | 550 | 0.441925 | 0.0201328 | 803.5
2960475 | 지상 10층 | 지상 10층 | 2960446 | 550 | 0.441925 | 0.0201328 | 803.5
2960726 | 지상 10층 | 지상 10층 | 2960446 | 550 | 0.441925 | 0.0201328 | 803.5
2960486 | 지상 10층 | 지상 10층 | 2960446 | 550 | 0.441925 | 0.0201328 | 803.5
2960735 | 지상 10층 | 지상 10층 | 2960446 | 550 | 0.441925 | 0.0201328 | 803.5
2960497 | 지상 10층 | 지상 10층 | 2960446 | 550 | 0.441925 | 0.0201328 | 803.5
2960744 | 지상 10층 | 지상 10층 | 2960446 | 550 | 0.441925 | 0.0201328 | 803.5
2960519 | 지상 10층 | 지상 10층 | 2960446 | 550 | 0.40095 | 0.0185832 | 729
2960753 | 지상 10층 | 지상 10층 | 2960446 | 550 | 0.40095 | 0.0185832 | 729
2960530 | 지상 10층 | 지상 10층 | 2960446 | 550 | 0.40095 | 0.0185832 | 729
2960762 | 지상 10층 | 지상 10층 | 2960446 | 550 | 0.40095 | 0.0185832 | 729
2960541 | 지상 10층 | 지상 10층 | 2960446 | 550 | 0.40095 | 0.0185832 | 729
2960771 | 지상 10층 | 지상 10층 | 2960446 | 550 | 0.40095 | 0.0185832 | 729
2960552 | 지상 10층 | 지상 10층 | 2960446 | 550 | 0.40095 | 0.0185832 | 729
2960780 | 지상 10층 | 지상 10층 | 2960446 | 550 | 0.40095 | 0.0185832 | 729
2960574 | 지상 10층 | 지상 10층 | 2960446 | 550 | 0.394075 | 0.0183232 | 716.5
2960789 | 지상 10층 | 지상 10층 | 2960446 | 550 | 0.394075 | 0.0183232 | 716.5
2960585 | 지상 10층 | 지상 10층 | 2960446 | 550 | 0.394075 | 0.0183232 | 716.5
2960798 | 지상 10층 | 지상 10층 | 2960446 | 550 | 0.394075 | 0.0183232 | 716.5
2960596 | 지상 10층 | 지상 10층 | 2960446 | 550 | 0.394075 | 0.0183232 | 716.5
2960807 | 지상 10층 | 지상 10층 | 2960446 | 550 | 0.394075 | 0.0183232 | 716.5
2960607 | 지상 10층 | 지상 10층 | 2960446 | 550 | 0.394075 | 0.0183232 | 716.5
2960816 | 지상 10층 | 지상 10층 | 2960446 | 550 | 0.394075 | 0.0183232 | 716.5
2960629 | 지상 10층 | 지상 10층 | 2960446 | 550 | 0.395096 | 0.0183618 | 718.357
2960825 | 지상 10층 | 지상 10층 | 2960446 | 550 | 0.395096 | 0.0183618 | 718.357
2960640 | 지상 10층 | 지상 10층 | 2960446 | 550 | 0.395096 | 0.0183618 | 718.357
2960834 | 지상 10층 | 지상 10층 | 2960446 | 550 | 0.395096 | 0.0183618 | 718.357
2960651 | 지상 10층 | 지상 10층 | 2960446 | 550 | 0.395096 | 0.0183618 | 718.357
2960843 | 지상 10층 | 지상 10층 | 2960446 | 550 | 0.395096 | 0.0183618 | 718.357
2960662 | 지상 10층 | 지상 10층 | 2960446 | 550 | 0.395096 | 0.0183618 | 718.357
2960852 | 지상 10층 | 지상 10층 | 2960446 | 550 | 0.395096 | 0.0183618 | 718.357
2960673 | 지상 10층 | 지상 10층 | 2960446 | 550 | 0.395096 | 0.0183618 | 718.357
2960861 | 지상 10층 | 지상 10층 | 2960446 | 550 | 0.395096 | 0.0183618 | 718.357
2960684 | 지상 10층 | 지상 10층 | 2960446 | 550 | 0.395096 | 0.0183618 | 718.357
2960870 | 지상 10층 | 지상 10층 | 2960446 | 550 | 0.395096 | 0.0183618 | 718.357
2960695 | 지상 10층 | 지상 10층 | 2960446 | 550 | 0.395096 | 0.0183618 | 718.357
2960879 | 지상 10층 | 지상 10층 | 2960446 | 550 | 0.395096 | 0.0183618 | 718.357
2970503 | 지상 10층 | 지상 10층 | 2970485 | 550 | 0.51975 | 0.023076 | 945
2970734 | 지상 10층 | 지상 10층 | 2970485 | 550 | 0.50325 | 0.022452 | 915
2970514 | 지상 10층 | 지상 10층 | 2970485 | 550 | 0.50325 | 0.022452 | 915
2970743 | 지상 10층 | 지상 10층 | 2970485 | 550 | 0.50325 | 0.022452 | 915
2970525 | 지상 10층 | 지상 10층 | 2970485 | 550 | 0.50325 | 0.022452 | 915
2970752 | 지상 10층 | 지상 10층 | 2970485 | 550 | 0.50325 | 0.022452 | 915
2970536 | 지상 10층 | 지상 10층 | 2970485 | 550 | 0.50325 | 0.022452 | 915
2970761 | 지상 10층 | 지상 10층 | 2970485 | 550 | 0.50325 | 0.022452 | 915
2970547 | 지상 10층 | 지상 10층 | 2970485 | 550 | 0.50325 | 0.022452 | 915
2970770 | 지상 10층 | 지상 10층 | 2970485 | 550 | 0.50325 | 0.022452 | 915
2970558 | 지상 10층 | 지상 10층 | 2970485 | 550 | 0.50325 | 0.022452 | 915
2970779 | 지상 10층 | 지상 10층 | 2970485 | 550 | 0.51975 | 0.023076 | 945
2970580 | 지상 10층 | 지상 10층 | 2970485 | 550 | 0.58025 | 0.025364 | 1055
2970788 | 지상 10층 | 지상 10층 | 2970485 | 550 | 0.59675 | 0.025988 | 1085
2970602 | 지상 10층 | 지상 10층 | 2970485 | 550 | 0.50325 | 0.022452 | 915
2970797 | 지상 10층 | 지상 10층 | 2970485 | 550 | 0.50325 | 0.022452 | 915
2970613 | 지상 10층 | 지상 10층 | 2970485 | 550 | 0.50325 | 0.022452 | 915
2970806 | 지상 10층 | 지상 10층 | 2970485 | 550 | 0.50325 | 0.022452 | 915
2970624 | 지상 10층 | 지상 10층 | 2970485 | 550 | 0.50325 | 0.022452 | 915
2970815 | 지상 10층 | 지상 10층 | 2970485 | 550 | 0.50325 | 0.022452 | 915
2970635 | 지상 10층 | 지상 10층 | 2970485 | 550 | 0.50325 | 0.022452 | 915
2970824 | 지상 10층 | 지상 10층 | 2970485 | 550 | 0.50325 | 0.022452 | 915
2970646 | 지상 10층 | 지상 10층 | 2970485 | 550 | 0.50325 | 0.022452 | 915
2970833 | 지상 10층 | 지상 10층 | 2970485 | 550 | 0.5005 | 0.022348 | 910
2970668 | 지상 10층 | 지상 10층 | 2970485 | 550 | 0.5335 | 0.023596 | 970
2970842 | 지상 10층 | 지상 10층 | 2970485 | 550 | 0.50325 | 0.022452 | 915
2970679 | 지상 10층 | 지상 10층 | 2970485 | 550 | 0.50325 | 0.022452 | 915
2970851 | 지상 10층 | 지상 10층 | 2970485 | 550 | 0.50325 | 0.022452 | 915
2970690 | 지상 10층 | 지상 10층 | 2970485 | 550 | 0.50325 | 0.022452 | 915
2970860 | 지상 10층 | 지상 10층 | 2970485 | 550 | 0.50325 | 0.022452 | 915
2970701 | 지상 10층 | 지상 10층 | 2970485 | 550 | 0.50325 | 0.022452 | 915
2970869 | 지상 10층 | 지상 10층 | 2970485 | 550 | 0.50325 | 0.022452 | 915
2970712 | 지상 10층 | 지상 10층 | 2970485 | 550 | 0.55825 | 0.024532 | 1015
2971598 | 지상 5층 | 지상 5층 | 2971239 | 550 | 0.488862 | 0.0219079 | 888.84
2974836 | 지상 5층 | 지상 5층 | 2971239 | 550 | 0.402512 | 0.0186423 | 731.839
2973908 | 지상 5층 | 지상 5층 | 2971239 | 550 | 0.402512 | 0.0186423 | 731.839
2974811 | 지상 5층 | 지상 5층 | 2971239 | 550 | 0.402512 | 0.0186423 | 731.839
2973814 | 지상 5층 | 지상 5층 | 2971239 | 550 | 0.402512 | 0.0186423 | 731.839
2974774 | 지상 5층 | 지상 5층 | 2971239 | 550 | 0.402512 | 0.0186423 | 731.839
2973740 | 지상 5층 | 지상 5층 | 2971239 | 550 | 0.402512 | 0.0186423 | 731.839
2974737 | 지상 5층 | 지상 5층 | 2971239 | 550 | 0.402512 | 0.0186423 | 731.839
2973690 | 지상 5층 | 지상 5층 | 2971239 | 550 | 0.402512 | 0.0186423 | 731.839
2974700 | 지상 5층 | 지상 5층 | 2971239 | 550 | 0.402512 | 0.0186423 | 731.839
2973518 | 지상 5층 | 지상 5층 | 2971239 | 550 | 0.40205 | 0.0186248 | 731
2974667 | 지상 5층 | 지상 5층 | 2971239 | 550 | 0.40205 | 0.0186248 | 731
2973438 | 지상 5층 | 지상 5층 | 2971239 | 550 | 0.40205 | 0.0186248 | 731
2974630 | 지상 5층 | 지상 5층 | 2971239 | 550 | 0.40205 | 0.0186248 | 731
2973322 | 지상 5층 | 지상 5층 | 2971239 | 550 | 0.40205 | 0.0186248 | 731
2974593 | 지상 5층 | 지상 5층 | 2971239 | 550 | 0.40205 | 0.0186248 | 731
2973220 | 지상 5층 | 지상 5층 | 2971239 | 550 | 0.40205 | 0.0186248 | 731
2974559 | 지상 5층 | 지상 5층 | 2971239 | 550 | 0.40205 | 0.0186248 | 731
2972995 | 지상 5층 | 지상 5층 | 2971239 | 550 | 0.388284 | 0.0181042 | 705.972
2974522 | 지상 5층 | 지상 5층 | 2971239 | 550 | 0.388284 | 0.0181042 | 705.972
2972883 | 지상 5층 | 지상 5층 | 2971239 | 550 | 0.388284 | 0.0181042 | 705.972
2974485 | 지상 5층 | 지상 5층 | 2971239 | 550 | 0.388284 | 0.0181042 | 705.972
2972769 | 지상 5층 | 지상 5층 | 2971239 | 550 | 0.388284 | 0.0181042 | 705.972
2974448 | 지상 5층 | 지상 5층 | 2971239 | 550 | 0.388284 | 0.0181042 | 705.972
2972663 | 지상 5층 | 지상 5층 | 2971239 | 550 | 0.388284 | 0.0181042 | 705.972
2974411 | 지상 5층 | 지상 5층 | 2971239 | 550 | 0.388284 | 0.0181042 | 705.972
2972569 | 지상 5층 | 지상 5층 | 2971239 | 550 | 0.388284 | 0.0181042 | 705.972
2974374 | 지상 5층 | 지상 5층 | 2971239 | 550 | 0.388284 | 0.0181042 | 705.972
2972474 | 지상 5층 | 지상 5층 | 2971239 | 550 | 0.388284 | 0.0181042 | 705.972
2974337 | 지상 5층 | 지상 5층 | 2971239 | 550 | 0.388284 | 0.0181042 | 705.972
2972377 | 지상 5층 | 지상 5층 | 2971239 | 550 | 0.388284 | 0.0181042 | 705.972
2974223 | 지상 5층 | 지상 5층 | 2971239 | 550 | 0.388284 | 0.0181042 | 705.972
2975049 | 지상 6층 | 지상 6층 | 2975042 | 550 | 0.485867 | 0.0217946 | 883.395
2975393 | 지상 6층 | 지상 6층 | 2975042 | 550 | 0.385 | 0.01798 | 700
2975247 | 지상 6층 | 지상 6층 | 2975042 | 550 | 0.40095 | 0.0185832 | 729
2975384 | 지상 6층 | 지상 6층 | 2975042 | 550 | 0.40095 | 0.0185832 | 729
2975236 | 지상 6층 | 지상 6층 | 2975042 | 550 | 0.40095 | 0.0185832 | 729
2975375 | 지상 6층 | 지상 6층 | 2975042 | 550 | 0.40095 | 0.0185832 | 729
2975225 | 지상 6층 | 지상 6층 | 2975042 | 550 | 0.40095 | 0.0185832 | 729
2975366 | 지상 6층 | 지상 6층 | 2975042 | 550 | 0.40095 | 0.0185832 | 729
2975214 | 지상 6층 | 지상 6층 | 2975042 | 550 | 0.40095 | 0.0185832 | 729
2975357 | 지상 6층 | 지상 6층 | 2975042 | 550 | 0.43395 | 0.0198312 | 789
2975192 | 지상 6층 | 지상 6층 | 2975042 | 550 | 0.4268 | 0.0195608 | 776
2975348 | 지상 6층 | 지상 6층 | 2975042 | 550 | 0.3938 | 0.0183128 | 716
2975181 | 지상 6층 | 지상 6층 | 2975042 | 550 | 0.3938 | 0.0183128 | 716
2975339 | 지상 6층 | 지상 6층 | 2975042 | 550 | 0.3938 | 0.0183128 | 716
2975170 | 지상 6층 | 지상 6층 | 2975042 | 550 | 0.3938 | 0.0183128 | 716
2975330 | 지상 6층 | 지상 6층 | 2975042 | 550 | 0.3938 | 0.0183128 | 716
2975159 | 지상 6층 | 지상 6층 | 2975042 | 550 | 0.3938 | 0.0183128 | 716
2975321 | 지상 6층 | 지상 6층 | 2975042 | 550 | 0.4268 | 0.0195608 | 776
2975137 | 지상 6층 | 지상 6층 | 2975042 | 550 | 0.4268 | 0.0195608 | 776
2975312 | 지상 6층 | 지상 6층 | 2975042 | 550 | 0.3938 | 0.0183128 | 716
2975126 | 지상 6층 | 지상 6층 | 2975042 | 550 | 0.3938 | 0.0183128 | 716
2975303 | 지상 6층 | 지상 6층 | 2975042 | 550 | 0.3938 | 0.0183128 | 716
2975115 | 지상 6층 | 지상 6층 | 2975042 | 550 | 0.3938 | 0.0183128 | 716
2975294 | 지상 6층 | 지상 6층 | 2975042 | 550 | 0.3938 | 0.0183128 | 716
2975104 | 지상 6층 | 지상 6층 | 2975042 | 550 | 0.3938 | 0.0183128 | 716
2975285 | 지상 6층 | 지상 6층 | 2975042 | 550 | 0.3938 | 0.0183128 | 716
2975093 | 지상 6층 | 지상 6층 | 2975042 | 550 | 0.3938 | 0.0183128 | 716
2975276 | 지상 6층 | 지상 6층 | 2975042 | 550 | 0.3938 | 0.0183128 | 716
2975082 | 지상 6층 | 지상 6층 | 2975042 | 550 | 0.3938 | 0.0183128 | 716
2975267 | 지상 6층 | 지상 6층 | 2975042 | 550 | 0.3938 | 0.0183128 | 716
2975071 | 지상 6층 | 지상 6층 | 2975042 | 550 | 0.3531 | 0.0167736 | 642
2975258 | 지상 6층 | 지상 6층 | 2975042 | 550 | 0.3861 | 0.0180216 | 702
2975409 | 지상 7층 | 지상 7층 | 2975402 | 550 | 0.385767 | 0.018009 | 701.395
2975753 | 지상 7층 | 지상 7층 | 2975402 | 550 | 0.385 | 0.01798 | 700
2975607 | 지상 7층 | 지상 7층 | 2975402 | 550 | 0.40095 | 0.0185832 | 729
2975744 | 지상 7층 | 지상 7층 | 2975402 | 550 | 0.40095 | 0.0185832 | 729
2975596 | 지상 7층 | 지상 7층 | 2975402 | 550 | 0.40095 | 0.0185832 | 729
2975735 | 지상 7층 | 지상 7층 | 2975402 | 550 | 0.40095 | 0.0185832 | 729
2975585 | 지상 7층 | 지상 7층 | 2975402 | 550 | 0.40095 | 0.0185832 | 729
2975726 | 지상 7층 | 지상 7층 | 2975402 | 550 | 0.40095 | 0.0185832 | 729
2975574 | 지상 7층 | 지상 7층 | 2975402 | 550 | 0.40095 | 0.0185832 | 729
2975717 | 지상 7층 | 지상 7층 | 2975402 | 550 | 0.43395 | 0.0198312 | 789
2975552 | 지상 7층 | 지상 7층 | 2975402 | 550 | 0.4268 | 0.0195608 | 776
2975708 | 지상 7층 | 지상 7층 | 2975402 | 550 | 0.3938 | 0.0183128 | 716
2975541 | 지상 7층 | 지상 7층 | 2975402 | 550 | 0.3938 | 0.0183128 | 716
2975699 | 지상 7층 | 지상 7층 | 2975402 | 550 | 0.3938 | 0.0183128 | 716
2975530 | 지상 7층 | 지상 7층 | 2975402 | 550 | 0.3938 | 0.0183128 | 716
2975690 | 지상 7층 | 지상 7층 | 2975402 | 550 | 0.3938 | 0.0183128 | 716
2975519 | 지상 7층 | 지상 7층 | 2975402 | 550 | 0.3938 | 0.0183128 | 716
2975681 | 지상 7층 | 지상 7층 | 2975402 | 550 | 0.4268 | 0.0195608 | 776
2975497 | 지상 7층 | 지상 7층 | 2975402 | 550 | 0.4268 | 0.0195608 | 776
2975672 | 지상 7층 | 지상 7층 | 2975402 | 550 | 0.3938 | 0.0183128 | 716
2975486 | 지상 7층 | 지상 7층 | 2975402 | 550 | 0.3938 | 0.0183128 | 716
2975663 | 지상 7층 | 지상 7층 | 2975402 | 550 | 0.3938 | 0.0183128 | 716
2975475 | 지상 7층 | 지상 7층 | 2975402 | 550 | 0.3938 | 0.0183128 | 716
2975654 | 지상 7층 | 지상 7층 | 2975402 | 550 | 0.3938 | 0.0183128 | 716
2975464 | 지상 7층 | 지상 7층 | 2975402 | 550 | 0.3938 | 0.0183128 | 716
2975645 | 지상 7층 | 지상 7층 | 2975402 | 550 | 0.3938 | 0.0183128 | 716
2975453 | 지상 7층 | 지상 7층 | 2975402 | 550 | 0.3938 | 0.0183128 | 716
2975636 | 지상 7층 | 지상 7층 | 2975402 | 550 | 0.3938 | 0.0183128 | 716
2975442 | 지상 7층 | 지상 7층 | 2975402 | 550 | 0.3938 | 0.0183128 | 716
2975627 | 지상 7층 | 지상 7층 | 2975402 | 550 | 0.3938 | 0.0183128 | 716
2975431 | 지상 7층 | 지상 7층 | 2975402 | 550 | 0.3531 | 0.0167736 | 642
2975618 | 지상 7층 | 지상 7층 | 2975402 | 550 | 0.3861 | 0.0180216 | 702
2975769 | 지상 8층 | 지상 8층 | 2975762 | 550 | 0.485867 | 0.0217946 | 883.395
2976113 | 지상 8층 | 지상 8층 | 2975762 | 550 | 0.385 | 0.01798 | 700
2975967 | 지상 8층 | 지상 8층 | 2975762 | 550 | 0.40095 | 0.0185832 | 729
2976104 | 지상 8층 | 지상 8층 | 2975762 | 550 | 0.40095 | 0.0185832 | 729
2975956 | 지상 8층 | 지상 8층 | 2975762 | 550 | 0.40095 | 0.0185832 | 729
2976095 | 지상 8층 | 지상 8층 | 2975762 | 550 | 0.40095 | 0.0185832 | 729
2975945 | 지상 8층 | 지상 8층 | 2975762 | 550 | 0.40095 | 0.0185832 | 729
2976086 | 지상 8층 | 지상 8층 | 2975762 | 550 | 0.40095 | 0.0185832 | 729
2975934 | 지상 8층 | 지상 8층 | 2975762 | 550 | 0.40095 | 0.0185832 | 729
2976077 | 지상 8층 | 지상 8층 | 2975762 | 550 | 0.43395 | 0.0198312 | 789
2975912 | 지상 8층 | 지상 8층 | 2975762 | 550 | 0.4268 | 0.0195608 | 776
2976068 | 지상 8층 | 지상 8층 | 2975762 | 550 | 0.3938 | 0.0183128 | 716
2975901 | 지상 8층 | 지상 8층 | 2975762 | 550 | 0.3938 | 0.0183128 | 716
2976059 | 지상 8층 | 지상 8층 | 2975762 | 550 | 0.3938 | 0.0183128 | 716
2975890 | 지상 8층 | 지상 8층 | 2975762 | 550 | 0.3938 | 0.0183128 | 716
2976050 | 지상 8층 | 지상 8층 | 2975762 | 550 | 0.3938 | 0.0183128 | 716
2975879 | 지상 8층 | 지상 8층 | 2975762 | 550 | 0.3938 | 0.0183128 | 716
2976041 | 지상 8층 | 지상 8층 | 2975762 | 550 | 0.4268 | 0.0195608 | 776
2975857 | 지상 8층 | 지상 8층 | 2975762 | 550 | 0.4268 | 0.0195608 | 776
2976032 | 지상 8층 | 지상 8층 | 2975762 | 550 | 0.3938 | 0.0183128 | 716
2975846 | 지상 8층 | 지상 8층 | 2975762 | 550 | 0.3938 | 0.0183128 | 716
2976023 | 지상 8층 | 지상 8층 | 2975762 | 550 | 0.3938 | 0.0183128 | 716
2975835 | 지상 8층 | 지상 8층 | 2975762 | 550 | 0.3938 | 0.0183128 | 716
2976014 | 지상 8층 | 지상 8층 | 2975762 | 550 | 0.3938 | 0.0183128 | 716
2975824 | 지상 8층 | 지상 8층 | 2975762 | 550 | 0.3938 | 0.0183128 | 716
2976005 | 지상 8층 | 지상 8층 | 2975762 | 550 | 0.3938 | 0.0183128 | 716
2975813 | 지상 8층 | 지상 8층 | 2975762 | 550 | 0.3938 | 0.0183128 | 716
2975996 | 지상 8층 | 지상 8층 | 2975762 | 550 | 0.3938 | 0.0183128 | 716
2975802 | 지상 8층 | 지상 8층 | 2975762 | 550 | 0.3938 | 0.0183128 | 716
2975987 | 지상 8층 | 지상 8층 | 2975762 | 550 | 0.3938 | 0.0183128 | 716
2975791 | 지상 8층 | 지상 8층 | 2975762 | 550 | 0.3531 | 0.0167736 | 642
2975978 | 지상 8층 | 지상 8층 | 2975762 | 550 | 0.3861 | 0.0180216 | 702
2976129 | 지상 9층 | 지상 9층 | 2976122 | 550 | 0.385767 | 0.018009 | 701.395
2976473 | 지상 9층 | 지상 9층 | 2976122 | 550 | 0.385 | 0.01798 | 700
2976327 | 지상 9층 | 지상 9층 | 2976122 | 550 | 0.40095 | 0.0185832 | 729
2976464 | 지상 9층 | 지상 9층 | 2976122 | 550 | 0.40095 | 0.0185832 | 729
2976316 | 지상 9층 | 지상 9층 | 2976122 | 550 | 0.40095 | 0.0185832 | 729
2976455 | 지상 9층 | 지상 9층 | 2976122 | 550 | 0.40095 | 0.0185832 | 729
2976305 | 지상 9층 | 지상 9층 | 2976122 | 550 | 0.40095 | 0.0185832 | 729
2976446 | 지상 9층 | 지상 9층 | 2976122 | 550 | 0.40095 | 0.0185832 | 729
2976294 | 지상 9층 | 지상 9층 | 2976122 | 550 | 0.40095 | 0.0185832 | 729
2976437 | 지상 9층 | 지상 9층 | 2976122 | 550 | 0.43395 | 0.0198312 | 789
2976272 | 지상 9층 | 지상 9층 | 2976122 | 550 | 0.4268 | 0.0195608 | 776
2976428 | 지상 9층 | 지상 9층 | 2976122 | 550 | 0.3938 | 0.0183128 | 716
2976261 | 지상 9층 | 지상 9층 | 2976122 | 550 | 0.3938 | 0.0183128 | 716
2976419 | 지상 9층 | 지상 9층 | 2976122 | 550 | 0.3938 | 0.0183128 | 716
2976250 | 지상 9층 | 지상 9층 | 2976122 | 550 | 0.3938 | 0.0183128 | 716
2976410 | 지상 9층 | 지상 9층 | 2976122 | 550 | 0.3938 | 0.0183128 | 716
2976239 | 지상 9층 | 지상 9층 | 2976122 | 550 | 0.3938 | 0.0183128 | 716
2976401 | 지상 9층 | 지상 9층 | 2976122 | 550 | 0.4268 | 0.0195608 | 776
2976217 | 지상 9층 | 지상 9층 | 2976122 | 550 | 0.4268 | 0.0195608 | 776
2976392 | 지상 9층 | 지상 9층 | 2976122 | 550 | 0.3938 | 0.0183128 | 716
2976206 | 지상 9층 | 지상 9층 | 2976122 | 550 | 0.3938 | 0.0183128 | 716
2976383 | 지상 9층 | 지상 9층 | 2976122 | 550 | 0.3938 | 0.0183128 | 716
2976195 | 지상 9층 | 지상 9층 | 2976122 | 550 | 0.3938 | 0.0183128 | 716
2976374 | 지상 9층 | 지상 9층 | 2976122 | 550 | 0.3938 | 0.0183128 | 716
2976184 | 지상 9층 | 지상 9층 | 2976122 | 550 | 0.3938 | 0.0183128 | 716
2976365 | 지상 9층 | 지상 9층 | 2976122 | 550 | 0.3938 | 0.0183128 | 716
2976173 | 지상 9층 | 지상 9층 | 2976122 | 550 | 0.3938 | 0.0183128 | 716
2976356 | 지상 9층 | 지상 9층 | 2976122 | 550 | 0.3938 | 0.0183128 | 716
2976162 | 지상 9층 | 지상 9층 | 2976122 | 550 | 0.3938 | 0.0183128 | 716
2976347 | 지상 9층 | 지상 9층 | 2976122 | 550 | 0.3938 | 0.0183128 | 716
2976151 | 지상 9층 | 지상 9층 | 2976122 | 550 | 0.3531 | 0.0167736 | 642
2976338 | 지상 9층 | 지상 9층 | 2976122 | 550 | 0.3861 | 0.0180216 | 702
2976489 | 지상 10층 | 지상 10층 | 2976482 | 550 | 0.495767 | 0.022169 | 901.395
2976833 | 지상 10층 | 지상 10층 | 2976482 | 550 | 0.385 | 0.01798 | 700
2976687 | 지상 10층 | 지상 10층 | 2976482 | 550 | 0.40095 | 0.0185832 | 729
2976824 | 지상 10층 | 지상 10층 | 2976482 | 550 | 0.40095 | 0.0185832 | 729
2976676 | 지상 10층 | 지상 10층 | 2976482 | 550 | 0.40095 | 0.0185832 | 729
2976815 | 지상 10층 | 지상 10층 | 2976482 | 550 | 0.40095 | 0.0185832 | 729
2976665 | 지상 10층 | 지상 10층 | 2976482 | 550 | 0.40095 | 0.0185832 | 729
2976806 | 지상 10층 | 지상 10층 | 2976482 | 550 | 0.40095 | 0.0185832 | 729
2976654 | 지상 10층 | 지상 10층 | 2976482 | 550 | 0.40095 | 0.0185832 | 729
2976797 | 지상 10층 | 지상 10층 | 2976482 | 550 | 0.43395 | 0.0198312 | 789
2976632 | 지상 10층 | 지상 10층 | 2976482 | 550 | 0.4268 | 0.0195608 | 776
2976788 | 지상 10층 | 지상 10층 | 2976482 | 550 | 0.3938 | 0.0183128 | 716
2976621 | 지상 10층 | 지상 10층 | 2976482 | 550 | 0.3938 | 0.0183128 | 716
2976779 | 지상 10층 | 지상 10층 | 2976482 | 550 | 0.3938 | 0.0183128 | 716
2976610 | 지상 10층 | 지상 10층 | 2976482 | 550 | 0.3938 | 0.0183128 | 716
2976770 | 지상 10층 | 지상 10층 | 2976482 | 550 | 0.3938 | 0.0183128 | 716
2976599 | 지상 10층 | 지상 10층 | 2976482 | 550 | 0.3938 | 0.0183128 | 716
2976761 | 지상 10층 | 지상 10층 | 2976482 | 550 | 0.4268 | 0.0195608 | 776
2976577 | 지상 10층 | 지상 10층 | 2976482 | 550 | 0.4268 | 0.0195608 | 776
2976752 | 지상 10층 | 지상 10층 | 2976482 | 550 | 0.3938 | 0.0183128 | 716
2976566 | 지상 10층 | 지상 10층 | 2976482 | 550 | 0.3938 | 0.0183128 | 716
2976743 | 지상 10층 | 지상 10층 | 2976482 | 550 | 0.3938 | 0.0183128 | 716
2976555 | 지상 10층 | 지상 10층 | 2976482 | 550 | 0.3938 | 0.0183128 | 716
2976734 | 지상 10층 | 지상 10층 | 2976482 | 550 | 0.3938 | 0.0183128 | 716
2976544 | 지상 10층 | 지상 10층 | 2976482 | 550 | 0.3938 | 0.0183128 | 716
2976725 | 지상 10층 | 지상 10층 | 2976482 | 550 | 0.3938 | 0.0183128 | 716
2976533 | 지상 10층 | 지상 10층 | 2976482 | 550 | 0.3938 | 0.0183128 | 716
2976716 | 지상 10층 | 지상 10층 | 2976482 | 550 | 0.3938 | 0.0183128 | 716
2976522 | 지상 10층 | 지상 10층 | 2976482 | 550 | 0.3938 | 0.0183128 | 716
2976707 | 지상 10층 | 지상 10층 | 2976482 | 550 | 0.3938 | 0.0183128 | 716
2976511 | 지상 10층 | 지상 10층 | 2976482 | 550 | 0.3531 | 0.0167736 | 642
2976698 | 지상 10층 | 지상 10층 | 2976482 | 550 | 0.3861 | 0.0180216 | 702
5818123 | 지상 9층 | 지상 9층 | 5818108 | 550 | 0.51975 | 0.023076 | 945
5818354 | 지상 9층 | 지상 9층 | 5818108 | 550 | 0.50325 | 0.022452 | 915
5818134 | 지상 9층 | 지상 9층 | 5818108 | 550 | 0.50325 | 0.022452 | 915
5818363 | 지상 9층 | 지상 9층 | 5818108 | 550 | 0.50325 | 0.022452 | 915
5818145 | 지상 9층 | 지상 9층 | 5818108 | 550 | 0.50325 | 0.022452 | 915
5818372 | 지상 9층 | 지상 9층 | 5818108 | 550 | 0.50325 | 0.022452 | 915
5818156 | 지상 9층 | 지상 9층 | 5818108 | 550 | 0.50325 | 0.022452 | 915
5818381 | 지상 9층 | 지상 9층 | 5818108 | 550 | 0.50325 | 0.022452 | 915
5818167 | 지상 9층 | 지상 9층 | 5818108 | 550 | 0.50325 | 0.022452 | 915
5818390 | 지상 9층 | 지상 9층 | 5818108 | 550 | 0.50325 | 0.022452 | 915
5818178 | 지상 9층 | 지상 9층 | 5818108 | 550 | 0.50325 | 0.022452 | 915
5818399 | 지상 9층 | 지상 9층 | 5818108 | 550 | 0.51975 | 0.023076 | 945
5818200 | 지상 9층 | 지상 9층 | 5818108 | 550 | 0.58025 | 0.025364 | 1055
5818408 | 지상 9층 | 지상 9층 | 5818108 | 550 | 0.59675 | 0.025988 | 1085
5818222 | 지상 9층 | 지상 9층 | 5818108 | 550 | 0.50325 | 0.022452 | 915
5818417 | 지상 9층 | 지상 9층 | 5818108 | 550 | 0.50325 | 0.022452 | 915
5818233 | 지상 9층 | 지상 9층 | 5818108 | 550 | 0.50325 | 0.022452 | 915
5818426 | 지상 9층 | 지상 9층 | 5818108 | 550 | 0.50325 | 0.022452 | 915
5818244 | 지상 9층 | 지상 9층 | 5818108 | 550 | 0.50325 | 0.022452 | 915
5818435 | 지상 9층 | 지상 9층 | 5818108 | 550 | 0.50325 | 0.022452 | 915
5818255 | 지상 9층 | 지상 9층 | 5818108 | 550 | 0.50325 | 0.022452 | 915
5818444 | 지상 9층 | 지상 9층 | 5818108 | 550 | 0.50325 | 0.022452 | 915
5818266 | 지상 9층 | 지상 9층 | 5818108 | 550 | 0.50325 | 0.022452 | 915
5818453 | 지상 9층 | 지상 9층 | 5818108 | 550 | 0.5005 | 0.022348 | 910
5818288 | 지상 9층 | 지상 9층 | 5818108 | 550 | 0.5335 | 0.023596 | 970
5818462 | 지상 9층 | 지상 9층 | 5818108 | 550 | 0.50325 | 0.022452 | 915
5818299 | 지상 9층 | 지상 9층 | 5818108 | 550 | 0.50325 | 0.022452 | 915
5818471 | 지상 9층 | 지상 9층 | 5818108 | 550 | 0.50325 | 0.022452 | 915
5818310 | 지상 9층 | 지상 9층 | 5818108 | 550 | 0.50325 | 0.022452 | 915
5818480 | 지상 9층 | 지상 9층 | 5818108 | 550 | 0.50325 | 0.022452 | 915
5818321 | 지상 9층 | 지상 9층 | 5818108 | 550 | 0.50325 | 0.022452 | 915
5818489 | 지상 9층 | 지상 9층 | 5818108 | 550 | 0.50325 | 0.022452 | 915
5818332 | 지상 9층 | 지상 9층 | 5818108 | 550 | 0.55825 | 0.024532 | 1015
5818699 | 지상 9층 | 지상 9층 | 5818681 | 550 | 0.441925 | 0.0201328 | 803.5
5818952 | 지상 9층 | 지상 9층 | 5818681 | 550 | 0.441925 | 0.0201328 | 803.5
5818710 | 지상 9층 | 지상 9층 | 5818681 | 550 | 0.441925 | 0.0201328 | 803.5
5818961 | 지상 9층 | 지상 9층 | 5818681 | 550 | 0.441925 | 0.0201328 | 803.5
5818721 | 지상 9층 | 지상 9층 | 5818681 | 550 | 0.441925 | 0.0201328 | 803.5
5818970 | 지상 9층 | 지상 9층 | 5818681 | 550 | 0.441925 | 0.0201328 | 803.5
5818732 | 지상 9층 | 지상 9층 | 5818681 | 550 | 0.441925 | 0.0201328 | 803.5
5818979 | 지상 9층 | 지상 9층 | 5818681 | 550 | 0.441925 | 0.0201328 | 803.5
5818754 | 지상 9층 | 지상 9층 | 5818681 | 550 | 0.40095 | 0.0185832 | 729
5818988 | 지상 9층 | 지상 9층 | 5818681 | 550 | 0.40095 | 0.0185832 | 729
5818765 | 지상 9층 | 지상 9층 | 5818681 | 550 | 0.40095 | 0.0185832 | 729
5818997 | 지상 9층 | 지상 9층 | 5818681 | 550 | 0.40095 | 0.0185832 | 729
5818776 | 지상 9층 | 지상 9층 | 5818681 | 550 | 0.40095 | 0.0185832 | 729
5819006 | 지상 9층 | 지상 9층 | 5818681 | 550 | 0.40095 | 0.0185832 | 729
5818787 | 지상 9층 | 지상 9층 | 5818681 | 550 | 0.40095 | 0.0185832 | 729
5819015 | 지상 9층 | 지상 9층 | 5818681 | 550 | 0.40095 | 0.0185832 | 729
5818809 | 지상 9층 | 지상 9층 | 5818681 | 550 | 0.394075 | 0.0183232 | 716.5
5819024 | 지상 9층 | 지상 9층 | 5818681 | 550 | 0.394075 | 0.0183232 | 716.5
5818820 | 지상 9층 | 지상 9층 | 5818681 | 550 | 0.394075 | 0.0183232 | 716.5
5819033 | 지상 9층 | 지상 9층 | 5818681 | 550 | 0.394075 | 0.0183232 | 716.5
5818831 | 지상 9층 | 지상 9층 | 5818681 | 550 | 0.394075 | 0.0183232 | 716.5
5819042 | 지상 9층 | 지상 9층 | 5818681 | 550 | 0.394075 | 0.0183232 | 716.5
5818842 | 지상 9층 | 지상 9층 | 5818681 | 550 | 0.394075 | 0.0183232 | 716.5
5819051 | 지상 9층 | 지상 9층 | 5818681 | 550 | 0.394075 | 0.0183232 | 716.5
5818864 | 지상 9층 | 지상 9층 | 5818681 | 550 | 0.395096 | 0.0183618 | 718.357
5819060 | 지상 9층 | 지상 9층 | 5818681 | 550 | 0.395096 | 0.0183618 | 718.357
5818875 | 지상 9층 | 지상 9층 | 5818681 | 550 | 0.395096 | 0.0183618 | 718.357
5819069 | 지상 9층 | 지상 9층 | 5818681 | 550 | 0.395096 | 0.0183618 | 718.357
5818886 | 지상 9층 | 지상 9층 | 5818681 | 550 | 0.395096 | 0.0183618 | 718.357
5819078 | 지상 9층 | 지상 9층 | 5818681 | 550 | 0.395096 | 0.0183618 | 718.357
5818897 | 지상 9층 | 지상 9층 | 5818681 | 550 | 0.395096 | 0.0183618 | 718.357
5819087 | 지상 9층 | 지상 9층 | 5818681 | 550 | 0.395096 | 0.0183618 | 718.357
5818908 | 지상 9층 | 지상 9층 | 5818681 | 550 | 0.395096 | 0.0183618 | 718.357
5819096 | 지상 9층 | 지상 9층 | 5818681 | 550 | 0.395096 | 0.0183618 | 718.357
5818919 | 지상 9층 | 지상 9층 | 5818681 | 550 | 0.395096 | 0.0183618 | 718.357
5819105 | 지상 9층 | 지상 9층 | 5818681 | 550 | 0.395096 | 0.0183618 | 718.357
5818930 | 지상 9층 | 지상 9층 | 5818681 | 550 | 0.395096 | 0.0183618 | 718.357
5819114 | 지상 9층 | 지상 9층 | 5818681 | 550 | 0.395096 | 0.0183618 | 718.357
5819269 | 지상 8층 | 지상 8층 | 5819254 | 550 | 0.51975 | 0.023076 | 945
5819500 | 지상 8층 | 지상 8층 | 5819254 | 550 | 0.50325 | 0.022452 | 915
5819280 | 지상 8층 | 지상 8층 | 5819254 | 550 | 0.50325 | 0.022452 | 915
5819509 | 지상 8층 | 지상 8층 | 5819254 | 550 | 0.50325 | 0.022452 | 915
5819291 | 지상 8층 | 지상 8층 | 5819254 | 550 | 0.50325 | 0.022452 | 915
5819518 | 지상 8층 | 지상 8층 | 5819254 | 550 | 0.50325 | 0.022452 | 915
5819302 | 지상 8층 | 지상 8층 | 5819254 | 550 | 0.50325 | 0.022452 | 915
5819527 | 지상 8층 | 지상 8층 | 5819254 | 550 | 0.50325 | 0.022452 | 915
5819313 | 지상 8층 | 지상 8층 | 5819254 | 550 | 0.50325 | 0.022452 | 915
5819536 | 지상 8층 | 지상 8층 | 5819254 | 550 | 0.50325 | 0.022452 | 915
5819324 | 지상 8층 | 지상 8층 | 5819254 | 550 | 0.50325 | 0.022452 | 915
5819545 | 지상 8층 | 지상 8층 | 5819254 | 550 | 0.51975 | 0.023076 | 945
5819346 | 지상 8층 | 지상 8층 | 5819254 | 550 | 0.58025 | 0.025364 | 1055
5819554 | 지상 8층 | 지상 8층 | 5819254 | 550 | 0.59675 | 0.025988 | 1085
5819368 | 지상 8층 | 지상 8층 | 5819254 | 550 | 0.50325 | 0.022452 | 915
5819563 | 지상 8층 | 지상 8층 | 5819254 | 550 | 0.50325 | 0.022452 | 915
5819379 | 지상 8층 | 지상 8층 | 5819254 | 550 | 0.50325 | 0.022452 | 915
5819572 | 지상 8층 | 지상 8층 | 5819254 | 550 | 0.50325 | 0.022452 | 915
5819390 | 지상 8층 | 지상 8층 | 5819254 | 550 | 0.50325 | 0.022452 | 915
5819581 | 지상 8층 | 지상 8층 | 5819254 | 550 | 0.50325 | 0.022452 | 915
5819401 | 지상 8층 | 지상 8층 | 5819254 | 550 | 0.50325 | 0.022452 | 915
5819590 | 지상 8층 | 지상 8층 | 5819254 | 550 | 0.50325 | 0.022452 | 915
5819412 | 지상 8층 | 지상 8층 | 5819254 | 550 | 0.50325 | 0.022452 | 915
5819599 | 지상 8층 | 지상 8층 | 5819254 | 550 | 0.5005 | 0.022348 | 910
5819434 | 지상 8층 | 지상 8층 | 5819254 | 550 | 0.5335 | 0.023596 | 970
5819608 | 지상 8층 | 지상 8층 | 5819254 | 550 | 0.50325 | 0.022452 | 915
5819445 | 지상 8층 | 지상 8층 | 5819254 | 550 | 0.50325 | 0.022452 | 915
5819617 | 지상 8층 | 지상 8층 | 5819254 | 550 | 0.50325 | 0.022452 | 915
5819456 | 지상 8층 | 지상 8층 | 5819254 | 550 | 0.50325 | 0.022452 | 915
5819626 | 지상 8층 | 지상 8층 | 5819254 | 550 | 0.50325 | 0.022452 | 915
5819467 | 지상 8층 | 지상 8층 | 5819254 | 550 | 0.50325 | 0.022452 | 915
5819635 | 지상 8층 | 지상 8층 | 5819254 | 550 | 0.50325 | 0.022452 | 915
5819478 | 지상 8층 | 지상 8층 | 5819254 | 550 | 0.55825 | 0.024532 | 1015
5819660 | 지상 8층 | 지상 8층 | 5819642 | 550 | 0.441925 | 0.0201328 | 803.5
5819913 | 지상 8층 | 지상 8층 | 5819642 | 550 | 0.441925 | 0.0201328 | 803.5
5819671 | 지상 8층 | 지상 8층 | 5819642 | 550 | 0.441925 | 0.0201328 | 803.5
5819922 | 지상 8층 | 지상 8층 | 5819642 | 550 | 0.441925 | 0.0201328 | 803.5
5819682 | 지상 8층 | 지상 8층 | 5819642 | 550 | 0.441925 | 0.0201328 | 803.5
5819931 | 지상 8층 | 지상 8층 | 5819642 | 550 | 0.441925 | 0.0201328 | 803.5
5819693 | 지상 8층 | 지상 8층 | 5819642 | 550 | 0.441925 | 0.0201328 | 803.5
5819940 | 지상 8층 | 지상 8층 | 5819642 | 550 | 0.441925 | 0.0201328 | 803.5
5819715 | 지상 8층 | 지상 8층 | 5819642 | 550 | 0.40095 | 0.0185832 | 729
5819949 | 지상 8층 | 지상 8층 | 5819642 | 550 | 0.40095 | 0.0185832 | 729
5819726 | 지상 8층 | 지상 8층 | 5819642 | 550 | 0.40095 | 0.0185832 | 729
5819958 | 지상 8층 | 지상 8층 | 5819642 | 550 | 0.40095 | 0.0185832 | 729
5819737 | 지상 8층 | 지상 8층 | 5819642 | 550 | 0.40095 | 0.0185832 | 729
5819967 | 지상 8층 | 지상 8층 | 5819642 | 550 | 0.40095 | 0.0185832 | 729
5819748 | 지상 8층 | 지상 8층 | 5819642 | 550 | 0.40095 | 0.0185832 | 729
5819976 | 지상 8층 | 지상 8층 | 5819642 | 550 | 0.40095 | 0.0185832 | 729
5819770 | 지상 8층 | 지상 8층 | 5819642 | 550 | 0.394075 | 0.0183232 | 716.5
5819985 | 지상 8층 | 지상 8층 | 5819642 | 550 | 0.394075 | 0.0183232 | 716.5
5819781 | 지상 8층 | 지상 8층 | 5819642 | 550 | 0.394075 | 0.0183232 | 716.5
5819994 | 지상 8층 | 지상 8층 | 5819642 | 550 | 0.394075 | 0.0183232 | 716.5
5819792 | 지상 8층 | 지상 8층 | 5819642 | 550 | 0.394075 | 0.0183232 | 716.5
5820003 | 지상 8층 | 지상 8층 | 5819642 | 550 | 0.394075 | 0.0183232 | 716.5
5819803 | 지상 8층 | 지상 8층 | 5819642 | 550 | 0.394075 | 0.0183232 | 716.5
5820012 | 지상 8층 | 지상 8층 | 5819642 | 550 | 0.394075 | 0.0183232 | 716.5
5819825 | 지상 8층 | 지상 8층 | 5819642 | 550 | 0.395096 | 0.0183618 | 718.357
5820021 | 지상 8층 | 지상 8층 | 5819642 | 550 | 0.395096 | 0.0183618 | 718.357
5819836 | 지상 8층 | 지상 8층 | 5819642 | 550 | 0.395096 | 0.0183618 | 718.357
5820030 | 지상 8층 | 지상 8층 | 5819642 | 550 | 0.395096 | 0.0183618 | 718.357
5819847 | 지상 8층 | 지상 8층 | 5819642 | 550 | 0.395096 | 0.0183618 | 718.357
5820039 | 지상 8층 | 지상 8층 | 5819642 | 550 | 0.395096 | 0.0183618 | 718.357
5819858 | 지상 8층 | 지상 8층 | 5819642 | 550 | 0.395096 | 0.0183618 | 718.357
5820048 | 지상 8층 | 지상 8층 | 5819642 | 550 | 0.395096 | 0.0183618 | 718.357
5819869 | 지상 8층 | 지상 8층 | 5819642 | 550 | 0.395096 | 0.0183618 | 718.357
5820057 | 지상 8층 | 지상 8층 | 5819642 | 550 | 0.395096 | 0.0183618 | 718.357
5819880 | 지상 8층 | 지상 8층 | 5819642 | 550 | 0.395096 | 0.0183618 | 718.357
5820066 | 지상 8층 | 지상 8층 | 5819642 | 550 | 0.395096 | 0.0183618 | 718.357
5819891 | 지상 8층 | 지상 8층 | 5819642 | 550 | 0.395096 | 0.0183618 | 718.357
5820075 | 지상 8층 | 지상 8층 | 5819642 | 550 | 0.395096 | 0.0183618 | 718.357
5820136 | 지상 7층 | 지상 7층 | 5820121 | 550 | 0.51975 | 0.023076 | 945
5820367 | 지상 7층 | 지상 7층 | 5820121 | 550 | 0.50325 | 0.022452 | 915
5820147 | 지상 7층 | 지상 7층 | 5820121 | 550 | 0.50325 | 0.022452 | 915
5820376 | 지상 7층 | 지상 7층 | 5820121 | 550 | 0.50325 | 0.022452 | 915
5820158 | 지상 7층 | 지상 7층 | 5820121 | 550 | 0.50325 | 0.022452 | 915
5820385 | 지상 7층 | 지상 7층 | 5820121 | 550 | 0.50325 | 0.022452 | 915
5820169 | 지상 7층 | 지상 7층 | 5820121 | 550 | 0.50325 | 0.022452 | 915
5820394 | 지상 7층 | 지상 7층 | 5820121 | 550 | 0.50325 | 0.022452 | 915
5820180 | 지상 7층 | 지상 7층 | 5820121 | 550 | 0.50325 | 0.022452 | 915
5820403 | 지상 7층 | 지상 7층 | 5820121 | 550 | 0.50325 | 0.022452 | 915
5820191 | 지상 7층 | 지상 7층 | 5820121 | 550 | 0.50325 | 0.022452 | 915
5820412 | 지상 7층 | 지상 7층 | 5820121 | 550 | 0.51975 | 0.023076 | 945
5820213 | 지상 7층 | 지상 7층 | 5820121 | 550 | 0.58025 | 0.025364 | 1055
5820421 | 지상 7층 | 지상 7층 | 5820121 | 550 | 0.59675 | 0.025988 | 1085
5820235 | 지상 7층 | 지상 7층 | 5820121 | 550 | 0.50325 | 0.022452 | 915
5820430 | 지상 7층 | 지상 7층 | 5820121 | 550 | 0.50325 | 0.022452 | 915
5820246 | 지상 7층 | 지상 7층 | 5820121 | 550 | 0.50325 | 0.022452 | 915
5820439 | 지상 7층 | 지상 7층 | 5820121 | 550 | 0.50325 | 0.022452 | 915
5820257 | 지상 7층 | 지상 7층 | 5820121 | 550 | 0.50325 | 0.022452 | 915
5820448 | 지상 7층 | 지상 7층 | 5820121 | 550 | 0.50325 | 0.022452 | 915
5820268 | 지상 7층 | 지상 7층 | 5820121 | 550 | 0.50325 | 0.022452 | 915
5820457 | 지상 7층 | 지상 7층 | 5820121 | 550 | 0.50325 | 0.022452 | 915
5820279 | 지상 7층 | 지상 7층 | 5820121 | 550 | 0.50325 | 0.022452 | 915
5820466 | 지상 7층 | 지상 7층 | 5820121 | 550 | 0.5005 | 0.022348 | 910
5820301 | 지상 7층 | 지상 7층 | 5820121 | 550 | 0.5335 | 0.023596 | 970
5820475 | 지상 7층 | 지상 7층 | 5820121 | 550 | 0.50325 | 0.022452 | 915
5820312 | 지상 7층 | 지상 7층 | 5820121 | 550 | 0.50325 | 0.022452 | 915
5820484 | 지상 7층 | 지상 7층 | 5820121 | 550 | 0.50325 | 0.022452 | 915
5820323 | 지상 7층 | 지상 7층 | 5820121 | 550 | 0.50325 | 0.022452 | 915
5820493 | 지상 7층 | 지상 7층 | 5820121 | 550 | 0.50325 | 0.022452 | 915
5820334 | 지상 7층 | 지상 7층 | 5820121 | 550 | 0.50325 | 0.022452 | 915
5820502 | 지상 7층 | 지상 7층 | 5820121 | 550 | 0.50325 | 0.022452 | 915
5820345 | 지상 7층 | 지상 7층 | 5820121 | 550 | 0.55825 | 0.024532 | 1015
5820527 | 지상 7층 | 지상 7층 | 5820509 | 550 | 0.441925 | 0.0201328 | 803.5
5820780 | 지상 7층 | 지상 7층 | 5820509 | 550 | 0.441925 | 0.0201328 | 803.5
5820538 | 지상 7층 | 지상 7층 | 5820509 | 550 | 0.441925 | 0.0201328 | 803.5
5820789 | 지상 7층 | 지상 7층 | 5820509 | 550 | 0.441925 | 0.0201328 | 803.5
5820549 | 지상 7층 | 지상 7층 | 5820509 | 550 | 0.441925 | 0.0201328 | 803.5
5820798 | 지상 7층 | 지상 7층 | 5820509 | 550 | 0.441925 | 0.0201328 | 803.5
5820560 | 지상 7층 | 지상 7층 | 5820509 | 550 | 0.441925 | 0.0201328 | 803.5
5820807 | 지상 7층 | 지상 7층 | 5820509 | 550 | 0.441925 | 0.0201328 | 803.5
5820582 | 지상 7층 | 지상 7층 | 5820509 | 550 | 0.40095 | 0.0185832 | 729
5820816 | 지상 7층 | 지상 7층 | 5820509 | 550 | 0.40095 | 0.0185832 | 729
5820593 | 지상 7층 | 지상 7층 | 5820509 | 550 | 0.40095 | 0.0185832 | 729
5820825 | 지상 7층 | 지상 7층 | 5820509 | 550 | 0.40095 | 0.0185832 | 729
5820604 | 지상 7층 | 지상 7층 | 5820509 | 550 | 0.40095 | 0.0185832 | 729
5820834 | 지상 7층 | 지상 7층 | 5820509 | 550 | 0.40095 | 0.0185832 | 729
5820615 | 지상 7층 | 지상 7층 | 5820509 | 550 | 0.40095 | 0.0185832 | 729
5820843 | 지상 7층 | 지상 7층 | 5820509 | 550 | 0.40095 | 0.0185832 | 729
5820637 | 지상 7층 | 지상 7층 | 5820509 | 550 | 0.394075 | 0.0183232 | 716.5
5820852 | 지상 7층 | 지상 7층 | 5820509 | 550 | 0.394075 | 0.0183232 | 716.5
5820648 | 지상 7층 | 지상 7층 | 5820509 | 550 | 0.394075 | 0.0183232 | 716.5
5820861 | 지상 7층 | 지상 7층 | 5820509 | 550 | 0.394075 | 0.0183232 | 716.5
5820659 | 지상 7층 | 지상 7층 | 5820509 | 550 | 0.394075 | 0.0183232 | 716.5
5820870 | 지상 7층 | 지상 7층 | 5820509 | 550 | 0.394075 | 0.0183232 | 716.5
5820670 | 지상 7층 | 지상 7층 | 5820509 | 550 | 0.394075 | 0.0183232 | 716.5
5820879 | 지상 7층 | 지상 7층 | 5820509 | 550 | 0.394075 | 0.0183232 | 716.5
5820692 | 지상 7층 | 지상 7층 | 5820509 | 550 | 0.395096 | 0.0183618 | 718.357
5820888 | 지상 7층 | 지상 7층 | 5820509 | 550 | 0.395096 | 0.0183618 | 718.357
5820703 | 지상 7층 | 지상 7층 | 5820509 | 550 | 0.395096 | 0.0183618 | 718.357
5820897 | 지상 7층 | 지상 7층 | 5820509 | 550 | 0.395096 | 0.0183618 | 718.357
5820714 | 지상 7층 | 지상 7층 | 5820509 | 550 | 0.395096 | 0.0183618 | 718.357
5820906 | 지상 7층 | 지상 7층 | 5820509 | 550 | 0.395096 | 0.0183618 | 718.357
5820725 | 지상 7층 | 지상 7층 | 5820509 | 550 | 0.395096 | 0.0183618 | 718.357
5820915 | 지상 7층 | 지상 7층 | 5820509 | 550 | 0.395096 | 0.0183618 | 718.357
5820736 | 지상 7층 | 지상 7층 | 5820509 | 550 | 0.395096 | 0.0183618 | 718.357
5820924 | 지상 7층 | 지상 7층 | 5820509 | 550 | 0.395096 | 0.0183618 | 718.357
5820747 | 지상 7층 | 지상 7층 | 5820509 | 550 | 0.395096 | 0.0183618 | 718.357
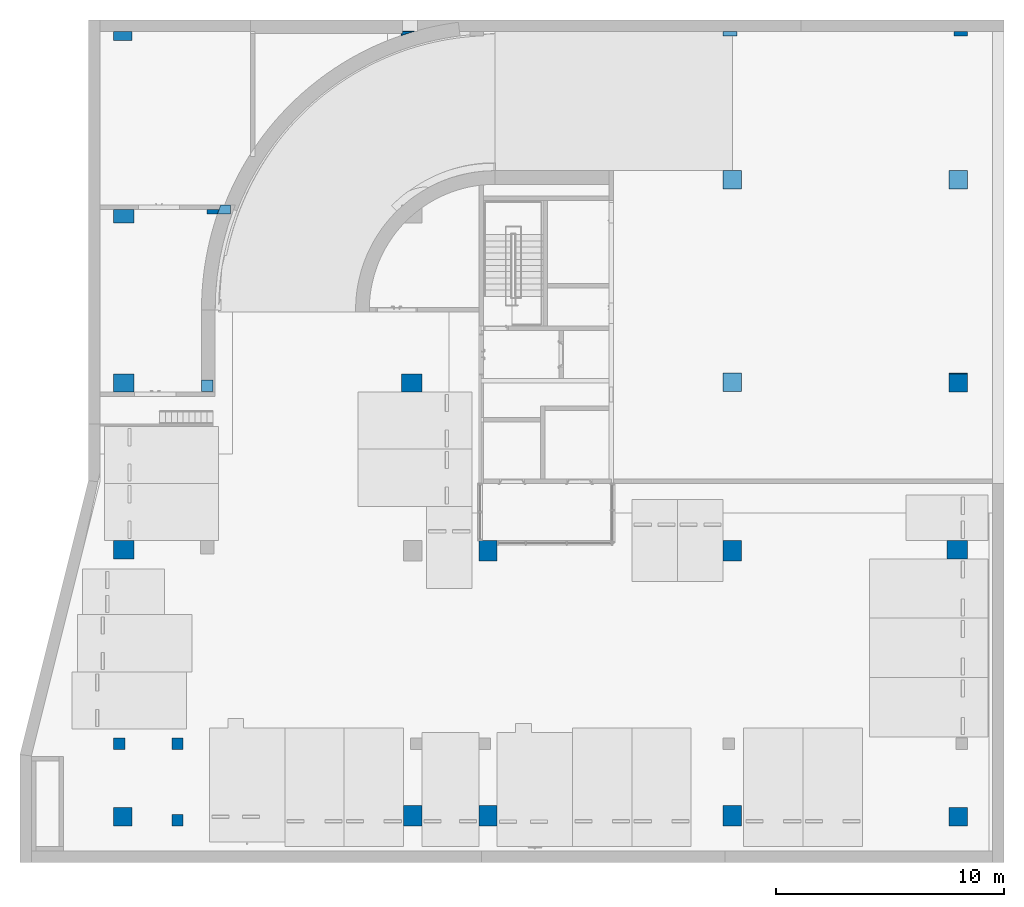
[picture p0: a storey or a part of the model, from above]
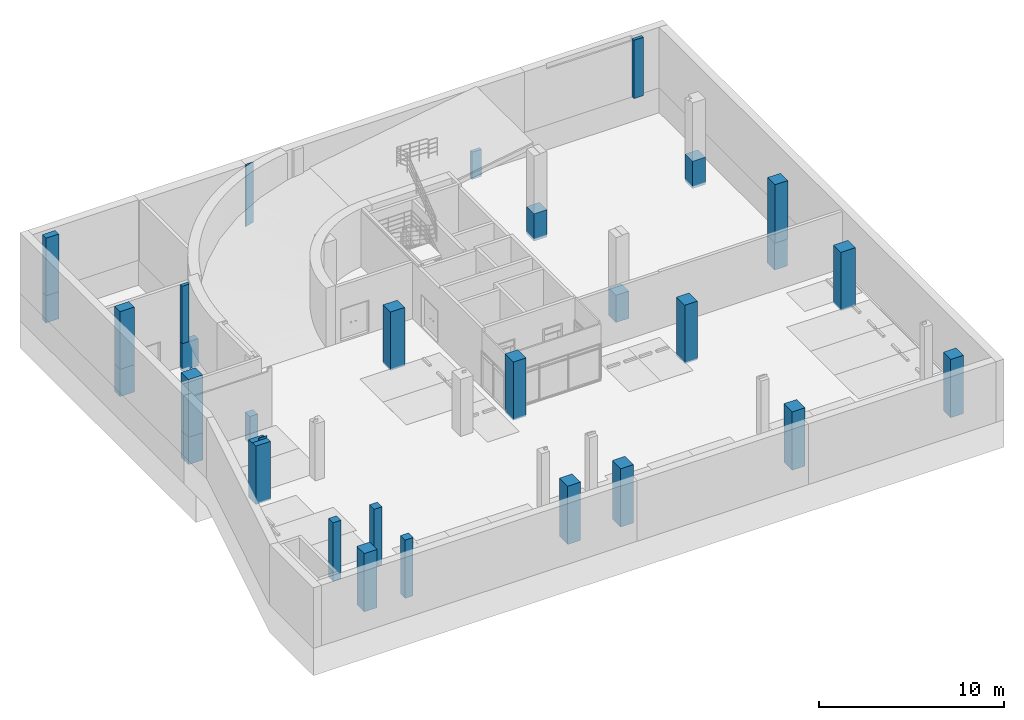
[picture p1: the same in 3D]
Properties of the parts of a building model (IFC2X3), part 32 of 39

# IfcPlate: CW410-프로젝트 창:CW410-프로젝트 창 (하부개폐) (939)
Name (CW410-프로젝트 창:CW410-프로젝트 창 (하부개폐):...) | In | 레벨 | 호스트 ID | 높이 (mm) | 면적 (m2) | 체적 (m3) = NetVolume (m3) | 폭 (mm)
5820933 | 지상 7층 | 지상 7층 | 5820509 | 550 | 0.395096 | 0.0183618 | 718.357
5820758 | 지상 7층 | 지상 7층 | 5820509 | 550 | 0.395096 | 0.0183618 | 718.357
5820942 | 지상 7층 | 지상 7층 | 5820509 | 550 | 0.395096 | 0.0183618 | 718.357
5821024 | 지상 6층 | 지상 6층 | 5821009 | 550 | 0.51975 | 0.023076 | 945
5821255 | 지상 6층 | 지상 6층 | 5821009 | 550 | 0.50325 | 0.022452 | 915
5821035 | 지상 6층 | 지상 6층 | 5821009 | 550 | 0.50325 | 0.022452 | 915
5821264 | 지상 6층 | 지상 6층 | 5821009 | 550 | 0.50325 | 0.022452 | 915
5821046 | 지상 6층 | 지상 6층 | 5821009 | 550 | 0.50325 | 0.022452 | 915
5821273 | 지상 6층 | 지상 6층 | 5821009 | 550 | 0.50325 | 0.022452 | 915
5821057 | 지상 6층 | 지상 6층 | 5821009 | 550 | 0.50325 | 0.022452 | 915
5821282 | 지상 6층 | 지상 6층 | 5821009 | 550 | 0.50325 | 0.022452 | 915
5821068 | 지상 6층 | 지상 6층 | 5821009 | 550 | 0.50325 | 0.022452 | 915
5821291 | 지상 6층 | 지상 6층 | 5821009 | 550 | 0.50325 | 0.022452 | 915
5821079 | 지상 6층 | 지상 6층 | 5821009 | 550 | 0.50325 | 0.022452 | 915
5821300 | 지상 6층 | 지상 6층 | 5821009 | 550 | 0.51975 | 0.023076 | 945
5821101 | 지상 6층 | 지상 6층 | 5821009 | 550 | 0.58025 | 0.025364 | 1055
5821309 | 지상 6층 | 지상 6층 | 5821009 | 550 | 0.59675 | 0.025988 | 1085
5821123 | 지상 6층 | 지상 6층 | 5821009 | 550 | 0.50325 | 0.022452 | 915
5821318 | 지상 6층 | 지상 6층 | 5821009 | 550 | 0.50325 | 0.022452 | 915
5821134 | 지상 6층 | 지상 6층 | 5821009 | 550 | 0.50325 | 0.022452 | 915
5821327 | 지상 6층 | 지상 6층 | 5821009 | 550 | 0.50325 | 0.022452 | 915
5821145 | 지상 6층 | 지상 6층 | 5821009 | 550 | 0.50325 | 0.022452 | 915
5821336 | 지상 6층 | 지상 6층 | 5821009 | 550 | 0.50325 | 0.022452 | 915
5821156 | 지상 6층 | 지상 6층 | 5821009 | 550 | 0.50325 | 0.022452 | 915
5821345 | 지상 6층 | 지상 6층 | 5821009 | 550 | 0.50325 | 0.022452 | 915
5821167 | 지상 6층 | 지상 6층 | 5821009 | 550 | 0.50325 | 0.022452 | 915
5821354 | 지상 6층 | 지상 6층 | 5821009 | 550 | 0.5005 | 0.022348 | 910
5821189 | 지상 6층 | 지상 6층 | 5821009 | 550 | 0.5335 | 0.023596 | 970
5821363 | 지상 6층 | 지상 6층 | 5821009 | 550 | 0.50325 | 0.022452 | 915
5821200 | 지상 6층 | 지상 6층 | 5821009 | 550 | 0.50325 | 0.022452 | 915
5821372 | 지상 6층 | 지상 6층 | 5821009 | 550 | 0.50325 | 0.022452 | 915
5821211 | 지상 6층 | 지상 6층 | 5821009 | 550 | 0.50325 | 0.022452 | 915
5821381 | 지상 6층 | 지상 6층 | 5821009 | 550 | 0.50325 | 0.022452 | 915
5821222 | 지상 6층 | 지상 6층 | 5821009 | 550 | 0.50325 | 0.022452 | 915
5821390 | 지상 6층 | 지상 6층 | 5821009 | 550 | 0.50325 | 0.022452 | 915
5821233 | 지상 6층 | 지상 6층 | 5821009 | 550 | 0.55825 | 0.024532 | 1015
5821415 | 지상 6층 | 지상 6층 | 5821397 | 550 | 0.441925 | 0.0201328 | 803.5
5821668 | 지상 6층 | 지상 6층 | 5821397 | 550 | 0.441925 | 0.0201328 | 803.5
5821426 | 지상 6층 | 지상 6층 | 5821397 | 550 | 0.441925 | 0.0201328 | 803.5
5821677 | 지상 6층 | 지상 6층 | 5821397 | 550 | 0.441925 | 0.0201328 | 803.5
5821437 | 지상 6층 | 지상 6층 | 5821397 | 550 | 0.441925 | 0.0201328 | 803.5
5821686 | 지상 6층 | 지상 6층 | 5821397 | 550 | 0.441925 | 0.0201328 | 803.5
5821448 | 지상 6층 | 지상 6층 | 5821397 | 550 | 0.441925 | 0.0201328 | 803.5
5821695 | 지상 6층 | 지상 6층 | 5821397 | 550 | 0.441925 | 0.0201328 | 803.5
5821470 | 지상 6층 | 지상 6층 | 5821397 | 550 | 0.40095 | 0.0185832 | 729
5821704 | 지상 6층 | 지상 6층 | 5821397 | 550 | 0.40095 | 0.0185832 | 729
5821481 | 지상 6층 | 지상 6층 | 5821397 | 550 | 0.40095 | 0.0185832 | 729
5821713 | 지상 6층 | 지상 6층 | 5821397 | 550 | 0.40095 | 0.0185832 | 729
5821492 | 지상 6층 | 지상 6층 | 5821397 | 550 | 0.40095 | 0.0185832 | 729
5821722 | 지상 6층 | 지상 6층 | 5821397 | 550 | 0.40095 | 0.0185832 | 729
5821503 | 지상 6층 | 지상 6층 | 5821397 | 550 | 0.40095 | 0.0185832 | 729
5821731 | 지상 6층 | 지상 6층 | 5821397 | 550 | 0.40095 | 0.0185832 | 729
5821525 | 지상 6층 | 지상 6층 | 5821397 | 550 | 0.394075 | 0.0183232 | 716.5
5821740 | 지상 6층 | 지상 6층 | 5821397 | 550 | 0.394075 | 0.0183232 | 716.5
5821536 | 지상 6층 | 지상 6층 | 5821397 | 550 | 0.394075 | 0.0183232 | 716.5
5821749 | 지상 6층 | 지상 6층 | 5821397 | 550 | 0.394075 | 0.0183232 | 716.5
5821547 | 지상 6층 | 지상 6층 | 5821397 | 550 | 0.394075 | 0.0183232 | 716.5
5821758 | 지상 6층 | 지상 6층 | 5821397 | 550 | 0.394075 | 0.0183232 | 716.5
5821558 | 지상 6층 | 지상 6층 | 5821397 | 550 | 0.394075 | 0.0183232 | 716.5
5821767 | 지상 6층 | 지상 6층 | 5821397 | 550 | 0.394075 | 0.0183232 | 716.5
5821580 | 지상 6층 | 지상 6층 | 5821397 | 550 | 0.395096 | 0.0183618 | 718.357
5821776 | 지상 6층 | 지상 6층 | 5821397 | 550 | 0.395096 | 0.0183618 | 718.357
5821591 | 지상 6층 | 지상 6층 | 5821397 | 550 | 0.395096 | 0.0183618 | 718.357
5821785 | 지상 6층 | 지상 6층 | 5821397 | 550 | 0.395096 | 0.0183618 | 718.357
5821602 | 지상 6층 | 지상 6층 | 5821397 | 550 | 0.395096 | 0.0183618 | 718.357
5821794 | 지상 6층 | 지상 6층 | 5821397 | 550 | 0.395096 | 0.0183618 | 718.357
5821613 | 지상 6층 | 지상 6층 | 5821397 | 550 | 0.395096 | 0.0183618 | 718.357
5821803 | 지상 6층 | 지상 6층 | 5821397 | 550 | 0.395096 | 0.0183618 | 718.357
5821624 | 지상 6층 | 지상 6층 | 5821397 | 550 | 0.395096 | 0.0183618 | 718.357
5821812 | 지상 6층 | 지상 6층 | 5821397 | 550 | 0.395096 | 0.0183618 | 718.357
5821635 | 지상 6층 | 지상 6층 | 5821397 | 550 | 0.395096 | 0.0183618 | 718.357
5821821 | 지상 6층 | 지상 6층 | 5821397 | 550 | 0.395096 | 0.0183618 | 718.357
5821646 | 지상 6층 | 지상 6층 | 5821397 | 550 | 0.395096 | 0.0183618 | 718.357
5821830 | 지상 6층 | 지상 6층 | 5821397 | 550 | 0.395096 | 0.0183618 | 718.357
5821893 | 지상 5층 | 지상 5층 | 5821878 | 550 | 0.51975 | 0.023076 | 945
5822124 | 지상 5층 | 지상 5층 | 5821878 | 550 | 0.50325 | 0.022452 | 915
5821904 | 지상 5층 | 지상 5층 | 5821878 | 550 | 0.50325 | 0.022452 | 915
5822133 | 지상 5층 | 지상 5층 | 5821878 | 550 | 0.50325 | 0.022452 | 915
5821915 | 지상 5층 | 지상 5층 | 5821878 | 550 | 0.50325 | 0.022452 | 915
5822142 | 지상 5층 | 지상 5층 | 5821878 | 550 | 0.50325 | 0.022452 | 915
5821926 | 지상 5층 | 지상 5층 | 5821878 | 550 | 0.50325 | 0.022452 | 915
5822151 | 지상 5층 | 지상 5층 | 5821878 | 550 | 0.50325 | 0.022452 | 915
5821937 | 지상 5층 | 지상 5층 | 5821878 | 550 | 0.50325 | 0.022452 | 915
5822160 | 지상 5층 | 지상 5층 | 5821878 | 550 | 0.50325 | 0.022452 | 915
5821948 | 지상 5층 | 지상 5층 | 5821878 | 550 | 0.50325 | 0.022452 | 915
5822169 | 지상 5층 | 지상 5층 | 5821878 | 550 | 0.51975 | 0.023076 | 945
5821970 | 지상 5층 | 지상 5층 | 5821878 | 550 | 0.58025 | 0.025364 | 1055
5822178 | 지상 5층 | 지상 5층 | 5821878 | 550 | 0.59675 | 0.025988 | 1085
5821992 | 지상 5층 | 지상 5층 | 5821878 | 550 | 0.50325 | 0.022452 | 915
5822187 | 지상 5층 | 지상 5층 | 5821878 | 550 | 0.50325 | 0.022452 | 915
5822003 | 지상 5층 | 지상 5층 | 5821878 | 550 | 0.50325 | 0.022452 | 915
5822196 | 지상 5층 | 지상 5층 | 5821878 | 550 | 0.50325 | 0.022452 | 915
5822014 | 지상 5층 | 지상 5층 | 5821878 | 550 | 0.50325 | 0.022452 | 915
5822205 | 지상 5층 | 지상 5층 | 5821878 | 550 | 0.50325 | 0.022452 | 915
5822025 | 지상 5층 | 지상 5층 | 5821878 | 550 | 0.50325 | 0.022452 | 915
5822214 | 지상 5층 | 지상 5층 | 5821878 | 550 | 0.50325 | 0.022452 | 915
5822036 | 지상 5층 | 지상 5층 | 5821878 | 550 | 0.50325 | 0.022452 | 915
5822223 | 지상 5층 | 지상 5층 | 5821878 | 550 | 0.5005 | 0.022348 | 910
5822058 | 지상 5층 | 지상 5층 | 5821878 | 550 | 0.5335 | 0.023596 | 970
5822232 | 지상 5층 | 지상 5층 | 5821878 | 550 | 0.50325 | 0.022452 | 915
5822069 | 지상 5층 | 지상 5층 | 5821878 | 550 | 0.50325 | 0.022452 | 915
5822241 | 지상 5층 | 지상 5층 | 5821878 | 550 | 0.50325 | 0.022452 | 915
5822080 | 지상 5층 | 지상 5층 | 5821878 | 550 | 0.50325 | 0.022452 | 915
5822250 | 지상 5층 | 지상 5층 | 5821878 | 550 | 0.50325 | 0.022452 | 915
5822091 | 지상 5층 | 지상 5층 | 5821878 | 550 | 0.50325 | 0.022452 | 915
5822259 | 지상 5층 | 지상 5층 | 5821878 | 550 | 0.50325 | 0.022452 | 915
5822102 | 지상 5층 | 지상 5층 | 5821878 | 550 | 0.55825 | 0.024532 | 1015
5822284 | 지상 5층 | 지상 5층 | 5822266 | 550 | 0.441925 | 0.0201328 | 803.5
5822537 | 지상 5층 | 지상 5층 | 5822266 | 550 | 0.441925 | 0.0201328 | 803.5
5822295 | 지상 5층 | 지상 5층 | 5822266 | 550 | 0.441925 | 0.0201328 | 803.5
5822546 | 지상 5층 | 지상 5층 | 5822266 | 550 | 0.441925 | 0.0201328 | 803.5
5822306 | 지상 5층 | 지상 5층 | 5822266 | 550 | 0.441925 | 0.0201328 | 803.5
5822555 | 지상 5층 | 지상 5층 | 5822266 | 550 | 0.441925 | 0.0201328 | 803.5
5822317 | 지상 5층 | 지상 5층 | 5822266 | 550 | 0.441925 | 0.0201328 | 803.5
5822564 | 지상 5층 | 지상 5층 | 5822266 | 550 | 0.441925 | 0.0201328 | 803.5
5822339 | 지상 5층 | 지상 5층 | 5822266 | 550 | 0.40095 | 0.0185832 | 729
5822573 | 지상 5층 | 지상 5층 | 5822266 | 550 | 0.40095 | 0.0185832 | 729
5822350 | 지상 5층 | 지상 5층 | 5822266 | 550 | 0.40095 | 0.0185832 | 729
5822582 | 지상 5층 | 지상 5층 | 5822266 | 550 | 0.40095 | 0.0185832 | 729
5822361 | 지상 5층 | 지상 5층 | 5822266 | 550 | 0.40095 | 0.0185832 | 729
5822591 | 지상 5층 | 지상 5층 | 5822266 | 550 | 0.40095 | 0.0185832 | 729
5822372 | 지상 5층 | 지상 5층 | 5822266 | 550 | 0.40095 | 0.0185832 | 729
5822600 | 지상 5층 | 지상 5층 | 5822266 | 550 | 0.40095 | 0.0185832 | 729
5822394 | 지상 5층 | 지상 5층 | 5822266 | 550 | 0.394075 | 0.0183232 | 716.5
5822609 | 지상 5층 | 지상 5층 | 5822266 | 550 | 0.394075 | 0.0183232 | 716.5
5822405 | 지상 5층 | 지상 5층 | 5822266 | 550 | 0.394075 | 0.0183232 | 716.5
5822618 | 지상 5층 | 지상 5층 | 5822266 | 550 | 0.394075 | 0.0183232 | 716.5
5822416 | 지상 5층 | 지상 5층 | 5822266 | 550 | 0.394075 | 0.0183232 | 716.5
5822627 | 지상 5층 | 지상 5층 | 5822266 | 550 | 0.394075 | 0.0183232 | 716.5
5822427 | 지상 5층 | 지상 5층 | 5822266 | 550 | 0.394075 | 0.0183232 | 716.5
5822636 | 지상 5층 | 지상 5층 | 5822266 | 550 | 0.394075 | 0.0183232 | 716.5
5822449 | 지상 5층 | 지상 5층 | 5822266 | 550 | 0.395096 | 0.0183618 | 718.357
5822645 | 지상 5층 | 지상 5층 | 5822266 | 550 | 0.395096 | 0.0183618 | 718.357
5822460 | 지상 5층 | 지상 5층 | 5822266 | 550 | 0.395096 | 0.0183618 | 718.357
5822654 | 지상 5층 | 지상 5층 | 5822266 | 550 | 0.395096 | 0.0183618 | 718.357
5822471 | 지상 5층 | 지상 5층 | 5822266 | 550 | 0.395096 | 0.0183618 | 718.357
5822663 | 지상 5층 | 지상 5층 | 5822266 | 550 | 0.395096 | 0.0183618 | 718.357
5822482 | 지상 5층 | 지상 5층 | 5822266 | 550 | 0.395096 | 0.0183618 | 718.357
5822672 | 지상 5층 | 지상 5층 | 5822266 | 550 | 0.395096 | 0.0183618 | 718.357
5822493 | 지상 5층 | 지상 5층 | 5822266 | 550 | 0.395096 | 0.0183618 | 718.357
5822681 | 지상 5층 | 지상 5층 | 5822266 | 550 | 0.395096 | 0.0183618 | 718.357
5822504 | 지상 5층 | 지상 5층 | 5822266 | 550 | 0.395096 | 0.0183618 | 718.357
5822690 | 지상 5층 | 지상 5층 | 5822266 | 550 | 0.395096 | 0.0183618 | 718.357
5822515 | 지상 5층 | 지상 5층 | 5822266 | 550 | 0.395096 | 0.0183618 | 718.357
5822699 | 지상 5층 | 지상 5층 | 5822266 | 550 | 0.395096 | 0.0183618 | 718.357

# IfcPlate: System Panel:Glazed (14)
Type - PredefinedType: CURTAIN_PANEL; Material: Glass
Type - ID 데이터 - 유형 이름: Glazed
Type - 구속조건 - 간격띄우기: 100 mm
Type - 기타 - 카테고리: 커튼월 패널; 패밀리 이름: System Panel
Type - 재료 및 마감재 - 재료: Glass
Type - 치수 - 두께: 100 mm
Type - 해석 특성 - 열 특성 정의 기준: 개략적 유형; 해석 시공: <없음>
Type - Pset_PlateCommon - IsExternal: no
공정 - 생성 공정: 새 구성
기타 - 유형: Glazed; 유형 ID: 7694674; 패밀리: System Panel; 패밀리 및 유형: System Panel: Glazed
치수 - 높이: 2075 mm
Pset_PlateCommon - Reference: Glazed
Pset_QuantityTakeOff - Reference: Glazed
Name (System Panel:Glazed:...) | In | 레벨 | 호스트 ID | 면적 (m2) | 체적 (m3) = NetVolume (m3) | 폭 (mm)
7728354 | 지상 3층 | 지상 3층 | 2921989 | 0.781957 | 0.0781957 | 376.847
7728355 | 지상 3층 | 지상 3층 | 2921989 | 0.878027 | 0.0878027 | 423.145
7728356 | 지상 9층 | 지상 9층 | 2922163 | 0.778125 | 0.0778125 | 375
7728357 | 지상 9층 | 지상 9층 | 2922163 | 0.881875 | 0.0881875 | 425
7728358 | 지상 10층 | 지상 10층 | 2922192 | 0.778125 | 0.0778125 | 375
7728359 | 지상 10층 | 지상 10층 | 2922192 | 0.881875 | 0.0881875 | 425
7728360 | 지상 5층 | 지상 5층 | 5398141 | 0.781957 | 0.0781957 | 376.847
7728361 | 지상 5층 | 지상 5층 | 5398141 | 0.878079 | 0.0878079 | 423.171
7728362 | 지상 6층 | 지상 6층 | 5398170 | 0.781921 | 0.0781921 | 376.829
7728363 | 지상 6층 | 지상 6층 | 5398170 | 0.878079 | 0.0878079 | 423.171
7728364 | 지상 7층 | 지상 7층 | 5398199 | 0.778125 | 0.0778125 | 375
7728365 | 지상 7층 | 지상 7층 | 5398199 | 0.971402 | 0.0971402 | 468.145
7728366 | 지상 8층 | 지상 8층 | 5398228 | 0.781957 | 0.0781957 | 376.847
7728367 | 지상 8층 | 지상 8층 | 5398228 | 0.878079 | 0.0878079 | 423.171

# IfcRailing: 난간:RL780-금속재 난간 (58)
Pset_QuantityTakeOff - Reference: RL780-금속재 난간
Pset_RailingCommon - IsExternal: no; Reference: RL780-금속재 난간; Height: 900 mm
공정 - 생성 공정: 새 구성
기타 - 유형: RL780-금속재 난간; 유형 ID: 6992761; 카테고리: 난간; 패밀리: 난간; 패밀리 및 유형: 난간: RL780-금속재 난간
ID 데이터(Type) - 단가: 0; 유형 이름: RL780-금속재 난간
기타(Type) - 카테고리: 난간; KBIMS-부위코드: E352; 조달청표준공사코드: AJC; 패밀리 이름: 난간
상단 난간(Type) - 높이: 900 mm; 상단 난간 사용: no
시공(Type) - 각도 결합: 수직/수평 세그먼트 추가; 계단참 높이 조정: 0 mm; 계단참 높이 조정 사용: no; 난간 높이: 1200 mm; 난간동자 간격띄우기: 0 mm; 난간 연결: 자르기; 접선 결합: 만날 때까지 난간 확장
핸드레일 1(Type) - 위치: 없음; sets with these values: 2
Name (난간:RL780-금속재 난간:...) | In | Material | Length (mm) = 길이 (mm) | 베이스 간격띄우기 (mm) | 경로에서 간격띄우기 (mm)
7504351 | 지상 4층 | KBIMS-난간 (11), KBIMS-금속재 (16) | 7876.3 | 0 | 50
7504501 | 지상 5층 | KBIMS-난간 (11), KBIMS-금속재 (16) | 7876.3 | 0 | 50
7504576 | 지상 6층 | KBIMS-난간 (11), KBIMS-금속재 (16) | 7876.3 | 0 | 50
7505143 | 지상 9층 | KBIMS-난간 (11), KBIMS-금속재 (16) | 8224.77 | 0 | 50
7505314 | 지상 1층 | KBIMS-난간 (10), KBIMS-금속재 (16) | 8210.26 | 0 | 50
7507499 | 지상 2층 | KBIMS-난간 (11), KBIMS-금속재 (16) | 8128.88 | 0 | 50
7507918 | 지상 3층 | KBIMS-난간 (11), KBIMS-금속재 (16) | 7876.34 | 0 | 50
7509672 | 지상 10층 | KBIMS-난간 (12), KBIMS-금속재 (16) | 10216 | 0 | 50
7517025 | 지상 8층 | KBIMS-난간 (11), KBIMS-금속재 (16) | 7901.31 | 0 | 50
7517082 | 지상 6층 | KBIMS-난간 (11), KBIMS-금속재 (16) | 7876.31 | 0 | 50
7524016 | 지상 10층 | KBIMS-난간 (12), KBIMS-금속재 (16) | 9593.4 | 0 | 50
7525882 | 지상 3층 | KBIMS-난간 (11), KBIMS-금속재 (16) | 7931.22 | 0 | 50
7525994 | 지상 4층 | KBIMS-난간 (11), KBIMS-금속재 (16) | 7931.22 | 0 | 50
7526106 | 지상 5층 | KBIMS-난간 (11), KBIMS-금속재 (16) | 7931.22 | 0 | 50
7526218 | 지상 6층 | KBIMS-난간 (11), KBIMS-금속재 (16) | 7931.22 | 0 | 50
7526330 | 지상 7층 | KBIMS-난간 (11), KBIMS-금속재 (16) | 7931.22 | 0 | 50
7526442 | 지상 8층 | KBIMS-난간 (11), KBIMS-금속재 (16) | 8011.22 | 0 | 50
7526554 | 지상 9층 | KBIMS-난간 (11), KBIMS-금속재 (16) | 8179.43 | 0 | 50
7528284 | 지상 2층 | KBIMS-난간 (11), KBIMS-금속재 (16) | 8176.62 | 0 | 50
7528998 | 지상 1층 | KBIMS-난간 (11), KBIMS-금속재 (16) | 8581.46 | 0 | 50
7530078 | 지하2층 | KBIMS-난간 (11), KBIMS-금속재 (16) | 9587.49 | 0 | 50
7530420 | 지하2층 | KBIMS-난간 (10), KBIMS-금속재 (16) | 7804 | 0 | 50
7708822 | 지상 2층 | KBIMS-난간 (3), KBIMS-금속재 (4) | 1540.01 | 0 | 0 | 구속조건 - 베이스 레벨: 지상 2층
7708930 | 지상 3층 | KBIMS-난간 (3), KBIMS-금속재 (4) | 1540.01 | 0 | 0 | 구속조건 - 베이스 레벨: 지상 3층
7708939 | 지상 4층 | KBIMS-난간 (3), KBIMS-금속재 (4) | 1540.01 | 0 | 0 | 구속조건 - 베이스 레벨: 지상 4층
7708949 | 지상 5층 | KBIMS-난간 (3), KBIMS-금속재 (4) | 1540 | 0 | 0 | 구속조건 - 베이스 레벨: 지상 5층
7708959 | 지상 6층 | KBIMS-난간 (3), KBIMS-금속재 (4) | 1540.01 | 0 | 0 | 구속조건 - 베이스 레벨: 지상 6층
7708969 | 지상 7층 | KBIMS-난간 (3), KBIMS-금속재 (4) | 1540.01 | 0 | 0 | 구속조건 - 베이스 레벨: 지상 7층
7708979 | 지상 8층 | KBIMS-난간 (3), KBIMS-금속재 (4) | 1540.01 | 0 | 0 | 구속조건 - 베이스 레벨: 지상 8층
7708989 | 지상 9층 | KBIMS-난간 (3), KBIMS-금속재 (4) | 1540 | 0 | 0 | 구속조건 - 베이스 레벨: 지상 9층
7708999 | 지상 10층 | KBIMS-난간 (3), KBIMS-금속재 (4) | 1540.01 | 80 | 0 | 구속조건 - 베이스 레벨: 지상 10층
8051634 | 지하2층 | KBIMS-난간 (17), KBIMS-금속재 (16) | 14620.7 | 0 | -50
8051820 | 지하1층 | KBIMS-난간 (17), KBIMS-금속재 (24) | 15547.8 | 0 | -50
8051928 | 지상 1층 | KBIMS-난간 (18), KBIMS-금속재 (16) | 16004.9 | 0 | -50
8052025 | 지상 2층 | KBIMS-난간 (18), KBIMS-금속재 (16) | 15927.4 | 0 | -50
8052101 | 지상 3층 | KBIMS-난간 (18), KBIMS-금속재 (16) | 15826.4 | 0 | -50
8052192 | 지상 4층 | KBIMS-난간 (18), KBIMS-금속재 (16) | 15826.4 | 0 | -50
8052503 | 지상 6층 | KBIMS-난간 (18), KBIMS-금속재 (16) | 15826.4 | 0 | -50
8052559 | 지상 5층 | KBIMS-난간 (18), KBIMS-금속재 (16) | 15826.4 | 0 | -50
8052671 | 지상 7층 | KBIMS-난간 (18), KBIMS-금속재 (16) | 15826.4 | 0 | -50
8052727 | 지상 8층 | KBIMS-난간 (18), KBIMS-금속재 (16) | 15826.4 | 0 | -50
8053080 | 지상 10층 | KBIMS-난간 (18), KBIMS-금속재 (16) | 16356.1 | 0 | -50
8053142 | 지상 9층 | KBIMS-난간 (18), KBIMS-금속재 (16) | 16009.2 | 0 | -50
8054053 | 지상 2층 | KBIMS-난간 (16), KBIMS-금속재 (12) | 14763.4 | 0 | -50
8054106 | 지상 3층 | KBIMS-난간 (16), KBIMS-금속재 (12) | 14536.4 | 0 | -50
8054156 | 지상 4층 | KBIMS-난간 (16), KBIMS-금속재 (12) | 14536.4 | 0 | -50
8054206 | 지상 5층 | KBIMS-난간 (16), KBIMS-금속재 (12) | 14536.4 | 0 | -50
8054256 | 지상 6층 | KBIMS-난간 (16), KBIMS-금속재 (12) | 14536.4 | 0 | -50
8054306 | 지상 7층 | KBIMS-난간 (16), KBIMS-금속재 (12) | 14536.4 | 0 | -50
8054356 | 지상 8층 | KBIMS-난간 (16), KBIMS-금속재 (12) | 14536.4 | 0 | -50
8054406 | 지상 9층 | KBIMS-난간 (16), KBIMS-금속재 (12) | 14763.4 | 0 | -50
8054456 | 지상 10층 | KBIMS-난간 (15), KBIMS-금속재 (12) | 13695.9 | 0 | -50
8055139 | 지상 1층 | KBIMS-난간 (16), KBIMS-금속재 (12) | 14840.8 | 0 | -50
8067941 | 지상 1층 | KBIMS-난간 (2), KBIMS-금속재 (4) | 1087.47 | 0 | 25.4
8067959 | 지상 1층 | KBIMS-난간 (3), KBIMS-금속재 (4) | 1701.39 | 0 | 50
8067980 | 지상 1층 | KBIMS-난간 (2), KBIMS-금속재 (4) | 680.555 | 0 | 25.4
8072955 | 지하2층 | KBIMS-난간 (4), KBIMS-금속재 (4) | 2846.05 | 0 | 50
8072959 | 지하2층 | KBIMS-난간 (4), KBIMS-금속재 (4) | 2846.05 | 0 | 50

# IfcRamp: 바닥:A1-12-09B-쇠흙손마감, 와이어매쉬(#8 150x150), 무근콘크리트, 에폭시페인트 (100mm) (2)
In: 지하2층
Pset_QuantityTakeOff - Reference: A1-12-09B-쇠흙손마감, 와이어매쉬(#8 150x150), 무근콘크리트, 에폭시페인트 (100mm)
Pset_RampCommon - IsExternal: no; Reference: A1-12-09B-쇠흙손마감, 와이어매쉬(#8 150x150), 무근콘크리트, 에폭시페인트 (100mm)
ID 데이터 - 연관 있음: no
공정 - 생성 공정: 새 구성
구속조건 - 레벨: 지하2층; 매스와 관련됨: no; 룸 경계: yes
구조 - 구조: no
기타 - 카테고리: 바닥; 패밀리: 바닥; 유형: A1-12-09B-쇠흙손마감, 와이어매쉬(#8 150x150), 무근콘크리트, 에폭시페인트 (100mm); 유형 ID: 6843374; 패밀리 및 유형: 바닥: A1-12-09B-쇠흙손마감, 와이어매쉬(#8 150x150), 무근콘크리트, 에폭시페인트 (100mm)
치수 - 두께: 100 mm
Name (바닥:A1-12-09B-쇠흙손마감, 와이어매쉬(#8 150x150), 무근콘크리트, 에폭시페인트 (100mm):...) | ShapeType | Material | 레벨로부터 높이 간격띄우기 (mm) | 둘레 (mm) | 면적 (m2) | 체적 (m3)
3674747 | SPIRAL_RAMP | SL671-에폭시페인트 바닥 (내산, 로울러칠, 3회), SL582-무근콘크리트 바닥 97mm, SL789-와이어매쉬 #8 150x150, SL555-쇠흙손마감 바닥 (콘크리트면) | 0 | 40769.4 | 87.4291 | 8.74291 | 슬래브 모양 편집 - 곡선 모서리 조건: 1
3674756 | STRAIGHT_RUN_RAMP | SL671-에폭시페인트 바닥 (내산, 로울러칠, 3회) 3 mm, SL582-무근콘크리트 바닥 97mm 95 mm, SL789-와이어매쉬 #8 150x150 1 mm, SL555-쇠흙손마감 바닥 (콘크리트면) 1 mm | 4100 | 33000.8 | 64.2989 | 6.42989

# IfcRamp: 바닥:A1-15-01B-화강석(물갈기) (80mm), 바닥:A1-15-01B-화강석(물갈기) (80mm):5364965
In: 지상 1층
ShapeType: STRAIGHT_RUN_RAMP; Material: SL312-화강석물갈기 바닥 (바탕30mm, 마감30mm) 80 mm
Pset_QuantityTakeOff - Reference: A1-15-01B-화강석(물갈기) (80mm)
Pset_RampCommon - IsExternal: no; Reference: A1-15-01B-화강석(물갈기) (80mm)
ID 데이터 - 연관 있음: no
공정 - 생성 공정: 새 구성
구속조건 - 매스와 관련됨: no; 레벨: 지상 1층; 룸 경계: no; 레벨로부터 높이 간격띄우기: 80 mm
구조 - 구조: no
기타 - 카테고리: 바닥; 패밀리: 바닥; 유형: A1-15-01B-화강석(물갈기) (80mm); 유형 ID: 6843992; 패밀리 및 유형: 바닥: A1-15-01B-화강석(물갈기) (80mm)
치수 - 두께: 80 mm; 둘레: 21086.9 mm; 면적: 20.1475 m2; 체적: 1.6118 m3

# IfcRamp: 바닥:RP111-철근콘크리트구조 램프 (돌음형) 300mm (2)
ShapeType: SPIRAL_RAMP; Material: KBIMS-콘크리트
Pset_QuantityTakeOff - Reference: RP111-철근콘크리트구조 램프 (돌음형) 300mm
Pset_RampCommon - IsExternal: no; Reference: RP111-철근콘크리트구조 램프 (돌음형) 300mm
ID 데이터 - 연관 있음: yes
공정 - 생성 공정: 새 구성
구속조건 - 매스와 관련됨: no; 룸 경계: yes
구조 - 구조: yes; 보강 철근 피복 - 다른 면: 보강 철근 피복 1 <25 mm>; 보강 철근 피복 - 상단 면: 보강 철근 피복 1 <25 mm>; 보강 철근 피복 - 하단 면: 보강 철근 피복 1 <25 mm>
기타 - 카테고리: 바닥; 패밀리: 바닥; 유형: RP111-철근콘크리트구조 램프 (돌음형) 300mm; 유형 ID: 7468756; 패밀리 및 유형: 바닥: RP111-철근콘크리트구조 램프 (돌음형) 300mm
슬래브 모양 편집 - 곡선 모서리 조건: 1
치수 - 두께: 300 mm
ID 데이터(Type) - 단가: 0; 유형 마크: RaS1; 유형 이름: RP111-철근콘크리트구조 램프 (돌음형) 300mm
그래픽(Type) - 거친 축척 채우기 색상: 0
기타(Type) - 내화구조여부: yes; 카테고리: 바닥; 주요구조부여부: yes; KBIMS-부위코드: E275; 조달청표준공사코드: AD; 패밀리 이름: 바닥
시공(Type) - 기능: 내부; 기본 두께: 300 mm
재료 및 마감재(Type) - 구조 재료: KBIMS-콘크리트
해석 특성(Type) - 거칠기: 1; 열 저항(R): 0.286807; 열 전달 계수(U): 3.48667 kg/K/s3; 열 질량: 453.33; 흡수율: 9290.3
Name (바닥:RP111-철근콘크리트구조 램프 (돌음형) 300mm:...) | In | 레벨로부터 높이 간격띄우기 (mm) | 레벨 | 둘레 (mm) | 면적 (m2) | 체적 (m3)
3096595 | 지하1층 | 0 | 지하1층 | 40769.4 | 86.7705 | 26.0311
3096769 | 지하2층 | -100 | 지하2층 | 40769 | 87.4257 | 26.2277

# IfcRamp: 바닥:RP111-철근콘크리트구조 램프 (직선형) 300mm (2)
ShapeType: STRAIGHT_RUN_RAMP; Material: KBIMS-콘크리트 300 mm
Pset_QuantityTakeOff - Reference: RP111-철근콘크리트구조 램프 (직선형) 300mm
Pset_RampCommon - IsExternal: no; Reference: RP111-철근콘크리트구조 램프 (직선형) 300mm
ID 데이터 - 연관 있음: yes
공정 - 생성 공정: 새 구성
구속조건 - 매스와 관련됨: no; 룸 경계: yes; 레벨로부터 높이 간격띄우기: 4000 mm
구조 - 구조: yes; 보강 철근 피복 - 다른 면: 보강 철근 피복 1 <25 mm>; 보강 철근 피복 - 상단 면: 보강 철근 피복 1 <25 mm>; 보강 철근 피복 - 하단 면: 보강 철근 피복 1 <25 mm>
기타 - 카테고리: 바닥; 패밀리: 바닥; 유형: RP111-철근콘크리트구조 램프 (직선형) 300mm; 유형 ID: 7468709; 패밀리 및 유형: 바닥: RP111-철근콘크리트구조 램프 (직선형) 300mm
치수 - 두께: 300 mm
ID 데이터(Type) - 단가: 0; 유형 마크: RaS1; 유형 이름: RP111-철근콘크리트구조 램프 (직선형) 300mm
그래픽(Type) - 거친 축척 채우기 색상: 0
기타(Type) - 내화구조여부: yes; 카테고리: 바닥; 주요구조부여부: yes; KBIMS-부위코드: E275; 조달청표준공사코드: AD; 패밀리 이름: 바닥
시공(Type) - 기능: 내부; 기본 두께: 300 mm
재료 및 마감재(Type) - 구조 재료: KBIMS-콘크리트
해석 특성(Type) - 거칠기: 1; 열 저항(R): 0.286807; 열 전달 계수(U): 3.48667 kg/K/s3; 열 질량: 453.33; 흡수율: 9290.3
Name (바닥:RP111-철근콘크리트구조 램프 (직선형) 300mm:...) | In | 레벨 | 둘레 (mm) | 면적 (m2) | 체적 (m3)
3096631 | 지하1층 | 지하1층 | 42200 | 93.6054 | 28.0816 | 슬래브 모양 편집 - 곡선 모서리 조건: 0
3684819 | 지하2층 | 지하2층 | 33000.8 | 64.2993 | 19.2898

# IfcRamp: 바닥:SL111-철근콘크리트구조 바닥 150mm_S3, 바닥:SL111-철근콘크리트구조 바닥 150mm_S3:5320732
In: 지상 1층
ShapeType: STRAIGHT_RUN_RAMP; Material: KBIMS-콘크리트 150 mm
Pset_QuantityTakeOff - Reference: SL111-철근콘크리트구조 바닥 150mm_S3
Pset_RampCommon - IsExternal: no; Reference: SL111-철근콘크리트구조 바닥 150mm_S3
ID 데이터 - 연관 있음: yes
공정 - 생성 공정: 새 구성
구속조건 - 레벨로부터 높이 간격띄우기: 0 mm; 매스와 관련됨: no; 룸 경계: yes; 레벨: 지상 1층
구조 - 구조: yes; 보강 철근 피복 - 다른 면: 보강 철근 피복 1 <25 mm>; 보강 철근 피복 - 상단 면: 보강 철근 피복 1 <25 mm>; 보강 철근 피복 - 하단 면: 보강 철근 피복 1 <25 mm>
기타 - 유형: SL111-철근콘크리트구조 바닥 150mm_S3; 유형 ID: 7622680; 카테고리: 바닥; 패밀리: 바닥; 패밀리 및 유형: 바닥: SL111-철근콘크리트구조 바닥 150mm_S3
치수 - 두께: 150 mm; 둘레: 21086.9 mm; 면적: 20.1475 m2; 체적: 3.02212 m3

# IfcRoof: 기본 지붕:RF111-철근콘크리트구조 지붕 (2)
In: 지상 1층
Material: KBIMS-철근콘크리트 200 mm
Pset_QuantityTakeOff - Reference: RF111-철근콘크리트구조 지붕
Pset_RoofCommon - IsExternal: yes; Reference: RF111-철근콘크리트구조 지붕
공정 - 생성 공정: 새 구성
구속조건 - 매스와 관련됨: no; 룸 경계: yes; 레벨로부터 베이스 간격띄우기: 3000 mm; 베이스 레벨: 지상 1층; 절단 간격띄우기: 0 mm
기타 - 유형: RF111-철근콘크리트구조 지붕; 유형 ID: 6900133; 카테고리: 지붕; 패밀리: 기본 지붕; 패밀리 및 유형: 기본 지붕: RF111-철근콘크리트구조 지붕
시공 - 서까래 절단: 수직 절단; 처마돌림 깊이: 0 mm; 최대 용마루 높이: 3200 mm
치수 - 경사: 0; 두께: 200 mm
Name (기본 지붕:RF111-철근콘크리트구조 지붕:...) | ProjectedArea (m2) = TotalArea (m2) = 면적 (m2) | 체적 (m3)
3113125 | 3.70364 | 0.740728
3157809 | 5.84544 | 1.16909

# IfcSlab: 기본 지붕:RF111-철근콘크리트구조 지붕 (2)
In: 지상 1층
Type - PredefinedType: ROOF
Type - ID 데이터 - 유형 이름: RF111-철근콘크리트구조 지붕
Type - 그래픽 - 거친 축척 채우기 색상: 0
Type - 기타 - 카테고리: 지붕; KBIMS-부위코드: E26; 조달청표준공사코드: AD; 패밀리 이름: 기본 지붕
Type - 시공 - 기본 두께: 200 mm
Type - 해석 특성 - 거칠기: 3; 열 저항(R): 0.191205; 열 전달 계수(U): 5.23 kg/K/s3; 열 질량: 302.22; 흡수율: 0.7
Type - Pset_SlabCommon - IsExternal: yes; ThermalTransmittance: 5.23 kg/K/s3
Material: KBIMS-철근콘크리트 200 mm
Pset_QuantityTakeOff - Reference: RF111-철근콘크리트구조 지붕; sets with these values: 2
Pset_SlabCommon - PitchAngle: 0 deg; Reference: RF111-철근콘크리트구조 지붕
Name (기본 지붕:RF111-철근콘크리트구조 지붕:...) | GrossArea (m2) | NetArea (m2) | GrossVolume (m3) | NetVolume (m3) | Perimeter (mm)
3113125 | 0.34408 | 3.70364 | 0.0688159 | 0.740728 | 9697.14
3157809 | 0.543059 | 5.84544 | 0.108612 | 1.16909 | 11111.4

# IfcSlab: 기초 슬래브:FT113-매트기초(기초슬래브)_MF1_1800mm (3)
In: 지하2층
Type - PredefinedType: BASESLAB; Material: KBIMS-콘크리트 1800 mm
Type - ID 데이터 - 단가: 0; 유형 이름: FT113-매트기초(기초슬래브)_MF1_1800mm
Type - 그래픽 - 거친 축척 채우기 색상: 0
Type - 기타 - 카테고리: 구조 기초; KBIMS-부위코드: E063; 내화구조여부: yes; 조달청표준공사코드: AD; 패밀리 이름: 기초 슬래브
Type - 시공 - 기본 두께: 1800 mm
Type - 재료 및 마감재 - 구조 재료: KBIMS-콘크리트
Type - 치수 - 기초 두께: 1800 mm
Type - 해석 특성 - 거칠기: 3; 열 저항(R): 1.72084; 열 전달 계수(U): 0.581111 kg/K/s3; 열 질량: 2719.98; 흡수율: 0.7
Type - Pset_SlabCommon - IsExternal: no; ThermalTransmittance: 0.581111 kg/K/s3
Pset_QuantityTakeOff - Reference: FT113-매트기초(기초슬래브)_MF1_1800mm; sets with these values: 2
Pset_SlabCommon - Reference: FT113-매트기초(기초슬래브)_MF1_1800mm; LoadBearing: yes; PitchAngle: 0 deg
BaseQuantities - Width: 1800 mm
ID 데이터 - 연관 있음: yes
공정 - 생성 공정: 새 구성
구속조건 - 레벨로부터 높이 간격띄우기: 0 mm; 매스와 관련됨: no
구조 - 구조: yes; 보강 철근 피복 - 다른 면: 보강 철근 피복 1 <25 mm>; 보강 철근 피복 - 상단 면: 보강 철근 피복 1 <25 mm>; 보강 철근 피복 - 하단 면: 보강 철근 피복 1 <25 mm>
기타 - 유형: FT113-매트기초(기초슬래브)_MF1_1800mm; 유형 ID: 6572322; 패밀리: 기초 슬래브; 패밀리 및 유형: 기초 슬래브: FT113-매트기초(기초슬래브)_MF1_1800mm
치수 - 두께: 1800 mm; 코어 두께: 1800 mm
Name (기초 슬래브:FT113-매트기초(기초슬래브)_MF1_1800mm:...) | GrossArea (m2) | NetArea (m2) = 면적 (m2) | GrossVolume (m3) = NetVolume (m3) = 체적 (m3) | Perimeter (mm) = 둘레 (mm) | 레벨 | 길이 (mm) | 상단 기준 레벨 (mm) = 상단 기준 레벨 측량 (mm) = 상단 코어의 입면도 (mm) | 폭 (mm) | 하단 기준 레벨 (mm) = 하단 기준 레벨 측량 (mm) = 하단 코어의 입면도 (mm)
2697895 | 970.705 | 970.705 | 1747.27 | 164209 | 지하2층 | 36400 | -10100 | 43100 | -11900
2698188 | 159.572 | 159.573 | 287.23 | 62368.2 | PIT | 19000 | -11900 | 14400 | -13700
3095024 | 479.123 | 479.123 | 862.421 | 91811.5 | PIT | 21603.9 | -11900 | 24301.8 | -13700

# IfcSlab: 바닥:(복합)SL111(150_S1)+A1-14-06B_철콘+테라조 (2)
In: 지상 10층
Type - PredefinedType: FLOOR; Material: SL341-테라조 바닥 (바탕48mm, 마감32mm) 80 mm, KBIMS-콘크리트 150 mm
Type - ID 데이터 - 단가: 0; 유형 마크: S1; 유형 이름: (복합)SL111(150_S1)+A1-14-06B_철콘+테라조
Type - 그래픽 - 거친 축척 채우기 색상: 0
Type - 기타 - 내화구조여부: yes; 카테고리: 바닥; 주요구조부여부: yes; KBIMS-부위코드: E251; 조달청표준공사코드: AD+AMB3032E; 패밀리 이름: 바닥
Type - 시공 - 기능: 내부; 기본 두께: 230 mm
Type - 재료 및 마감재 - 구조 재료: KBIMS-콘크리트
Type - 해석 특성 - 거칠기: 1; 열 저항(R): 0.143403; 열 전달 계수(U): 6.97333 kg/K/s3; 열 질량: 226.665; 흡수율: 9290.3
Type - Pset_SlabCommon - IsExternal: no; ThermalTransmittance: 6.97333 kg/K/s3
Pset_QuantityTakeOff - Reference: (복합)SL111(150_S1)+A1-14-06B_철콘+테라조; sets with these values: 2
Pset_SlabCommon - LoadBearing: yes; PitchAngle: 0 deg; Reference: (복합)SL111(150_S1)+A1-14-06B_철콘+테라조
BaseQuantities - Width: 230 mm
ID 데이터 - 연관 있음: yes
공정 - 생성 공정: 새 구성
구속조건 - 매스와 관련됨: no; 룸 경계: yes; 레벨: 지상 10층; 레벨로부터 높이 간격띄우기: 80 mm
구조 - 구조: yes; 보강 철근 피복 - 다른 면: 보강 철근 피복 1 <25 mm>; 보강 철근 피복 - 상단 면: 보강 철근 피복 1 <25 mm>; 보강 철근 피복 - 하단 면: 보강 철근 피복 1 <25 mm>
기타 - 패밀리: 바닥; 유형: (복합)SL111(150_S1)+A1-14-06B_철콘+테라조; 유형 ID: 7725765; 패밀리 및 유형: 바닥: (복합)SL111(150_S1)+A1-14-06B_철콘+테라조
치수 - 두께: 230 mm; 상단 기준 레벨: 38480 mm; 상단 기준 레벨 측량: 38480 mm; 상단 코어의 입면도: 38400 mm; 코어 두께: 150 mm; 하단 기준 레벨: 38250 mm; 하단 기준 레벨 측량: 38250 mm; 하단 코어의 입면도: 38250 mm
Name (바닥:(복합)SL111(150_S1)+A1-14-06B_철콘+테라조:...) | GrossArea (m2) = NetArea (m2) = 면적 (m2) | GrossVolume (m3) = NetVolume (m3) = 체적 (m3) | Perimeter (mm) = 둘레 (mm)
2765788 | 502.538 | 115.584 | 102800
2765800 | 98.44 | 22.6412 | 39800

# IfcSlab: 바닥:(복합)SL111(150_S2)+A1-14-06B_철콘+테라조, 바닥:(복합)SL111(150_S2)+A1-14-06B_철콘+테라조:2765793
In: 지상 10층
Type - PredefinedType: FLOOR; Material: SL341-테라조 바닥 (바탕48mm, 마감32mm) 80 mm, KBIMS-콘크리트 150 mm
Type - ID 데이터 - 단가: 0; 유형 마크: S2; 유형 이름: (복합)SL111(150_S2)+A1-14-06B_철콘+테라조
Type - 그래픽 - 거친 축척 채우기 색상: 0
Type - 기타 - 내화구조여부: yes; 카테고리: 바닥; 주요구조부여부: yes; KBIMS-부위코드: E251; 조달청표준공사코드: AD+AMB3032E; 패밀리 이름: 바닥
Type - 시공 - 기능: 내부; 기본 두께: 230 mm
Type - 재료 및 마감재 - 구조 재료: KBIMS-콘크리트
Type - 해석 특성 - 거칠기: 1; 열 저항(R): 0.143403; 열 전달 계수(U): 6.97333 kg/K/s3; 열 질량: 226.665; 흡수율: 9290.3
Type - Pset_SlabCommon - IsExternal: no; ThermalTransmittance: 6.97333 kg/K/s3
Pset_QuantityTakeOff - Reference: (복합)SL111(150_S2)+A1-14-06B_철콘+테라조; sets with these values: 2
Pset_SlabCommon - LoadBearing: yes; PitchAngle: 0 deg; Reference: (복합)SL111(150_S2)+A1-14-06B_철콘+테라조
BaseQuantities - GrossArea: 328.72 m2; NetArea: 328.72 m2; GrossVolume: 75.6056 m3; NetVolume: 75.6056 m3; Perimeter: 87200 mm; Width: 230 mm
ID 데이터 - 연관 있음: yes
공정 - 생성 공정: 새 구성
구속조건 - 매스와 관련됨: no; 룸 경계: yes; 레벨: 지상 10층; 레벨로부터 높이 간격띄우기: 80 mm
구조 - 구조: yes; 보강 철근 피복 - 다른 면: 보강 철근 피복 1 <25 mm>; 보강 철근 피복 - 상단 면: 보강 철근 피복 1 <25 mm>; 보강 철근 피복 - 하단 면: 보강 철근 피복 1 <25 mm>
기타 - 패밀리: 바닥; 유형: (복합)SL111(150_S2)+A1-14-06B_철콘+테라조; 유형 ID: 7725828; 패밀리 및 유형: 바닥: (복합)SL111(150_S2)+A1-14-06B_철콘+테라조
치수 - 두께: 230 mm; 둘레: 87200 mm; 면적: 328.72 m2; 상단 기준 레벨: 38480 mm; 상단 기준 레벨 측량: 38480 mm; 상단 코어의 입면도: 38400 mm; 체적: 75.6056 m3; 코어 두께: 150 mm; 하단 기준 레벨: 38250 mm; 하단 기준 레벨 측량: 38250 mm; 하단 코어의 입면도: 38250 mm

# IfcSlab: 바닥:(복합)SL111(150_S3)+A1-14-06B_철콘+테라조, 바닥:(복합)SL111(150_S3)+A1-14-06B_철콘+테라조:5403025
In: 지상 10층
Type - PredefinedType: FLOOR; Material: SL341-테라조 바닥 (바탕48mm, 마감32mm) 80 mm, KBIMS-콘크리트 150 mm
Type - ID 데이터 - 단가: 0; 유형 마크: S3; 유형 이름: (복합)SL111(150_S3)+A1-14-06B_철콘+테라조
Type - 그래픽 - 거친 축척 채우기 색상: 0
Type - 기타 - 내화구조여부: yes; 카테고리: 바닥; 주요구조부여부: yes; KBIMS-부위코드: E251; 조달청표준공사코드: AD+AMB3032E; 패밀리 이름: 바닥
Type - 시공 - 기능: 내부; 기본 두께: 230 mm
Type - 재료 및 마감재 - 구조 재료: KBIMS-콘크리트
Type - 해석 특성 - 거칠기: 1; 열 저항(R): 0.143403; 열 전달 계수(U): 6.97333 kg/K/s3; 열 질량: 226.665; 흡수율: 9290.3
Type - Pset_SlabCommon - IsExternal: no; ThermalTransmittance: 6.97333 kg/K/s3
Pset_QuantityTakeOff - Reference: (복합)SL111(150_S3)+A1-14-06B_철콘+테라조; sets with these values: 2
Pset_SlabCommon - PitchAngle: 0 deg; LoadBearing: no; Reference: (복합)SL111(150_S3)+A1-14-06B_철콘+테라조
BaseQuantities - GrossArea: 12.1821 m2; NetArea: 12.1821 m2; GrossVolume: 2.80188 m3; NetVolume: 2.80188 m3; Perimeter: 14799.8 mm; Width: 230 mm
ID 데이터 - 연관 있음: no
공정 - 생성 공정: 새 구성
구속조건 - 매스와 관련됨: no; 룸 경계: no; 레벨: 지상 10층; 레벨로부터 높이 간격띄우기: 80 mm
구조 - 구조: no
기타 - 패밀리: 바닥; 유형: (복합)SL111(150_S3)+A1-14-06B_철콘+테라조; 유형 ID: 7726310; 패밀리 및 유형: 바닥: (복합)SL111(150_S3)+A1-14-06B_철콘+테라조
치수 - 두께: 230 mm; 둘레: 14799.8 mm; 면적: 12.1821 m2; 상단 기준 레벨: 38480 mm; 체적: 2.80188 m3; 하단 기준 레벨: 38250 mm

# IfcSlab: 바닥:(복합)SL111(150_S3)+A1-15-01B_철콘+화강석, 바닥:(복합)SL111(150_S3)+A1-15-01B_철콘+화강석:2765807
In: 지상 10층
Type - PredefinedType: FLOOR; Material: SL312-화강석물갈기 바닥 (바탕30mm, 마감30mm) 80 mm, KBIMS-콘크리트 150 mm
Type - ID 데이터 - 단가: 0; 유형 마크: S3; 유형 이름: (복합)SL111(150_S3)+A1-15-01B_철콘+화강석
Type - 그래픽 - 거친 축척 채우기 색상: 0
Type - 기타 - 내화구조여부: yes; 카테고리: 바닥; 주요구조부여부: yes; KBIMS-부위코드: E251; 조달청표준공사코드: AD+AMB3211B; 패밀리 이름: 바닥
Type - 시공 - 기능: 내부; 기본 두께: 230 mm
Type - 재료 및 마감재 - 구조 재료: KBIMS-콘크리트
Type - 해석 특성 - 거칠기: 1; 열 저항(R): 0.166326; 열 전달 계수(U): 6.01229 kg/K/s3; 열 질량: 408.681; 흡수율: 9290.3
Type - Pset_SlabCommon - IsExternal: no; ThermalTransmittance: 6.01229 kg/K/s3
Pset_QuantityTakeOff - Reference: (복합)SL111(150_S3)+A1-15-01B_철콘+화강석; sets with these values: 2
Pset_SlabCommon - LoadBearing: yes; PitchAngle: 0 deg; Reference: (복합)SL111(150_S3)+A1-15-01B_철콘+화강석
BaseQuantities - GrossArea: 117.163 m2; NetArea: 117.163 m2; GrossVolume: 26.9475 m3; NetVolume: 26.9475 m3; Perimeter: 88899.8 mm; Width: 230 mm
ID 데이터 - 연관 있음: yes
공정 - 생성 공정: 새 구성
구속조건 - 매스와 관련됨: no; 룸 경계: yes; 레벨: 지상 10층; 레벨로부터 높이 간격띄우기: 80 mm
구조 - 구조: yes; 보강 철근 피복 - 다른 면: 보강 철근 피복 1 <25 mm>; 보강 철근 피복 - 상단 면: 보강 철근 피복 1 <25 mm>; 보강 철근 피복 - 하단 면: 보강 철근 피복 1 <25 mm>
기타 - 패밀리: 바닥; 유형: (복합)SL111(150_S3)+A1-15-01B_철콘+화강석; 유형 ID: 7726181; 패밀리 및 유형: 바닥: (복합)SL111(150_S3)+A1-15-01B_철콘+화강석
치수 - 두께: 230 mm; 둘레: 88899.8 mm; 면적: 117.163 m2; 상단 기준 레벨: 38480 mm; 상단 기준 레벨 측량: 38480 mm; 상단 코어의 입면도: 38400 mm; 체적: 26.9475 m3; 코어 두께: 150 mm; 하단 기준 레벨: 38250 mm; 하단 기준 레벨 측량: 38250 mm; 하단 코어의 입면도: 38250 mm

# IfcSlab: 바닥:(복합)SL111(150_S4)+A1-14-03A_철콘+도막방수 (2)
In: 지상 10층
Type - PredefinedType: FLOOR; Material: SL351-자기질타일 바닥 (바탕32mm, 압착8mm) 40 mm, SL553-보호모르타르 바닥 20mm 30 mm, SL521-도막방수 바닥 (비노출) 3mm 3 mm, SL551-시멘트모르타르 미장 바닥 17mm 17 mm, KBIMS-콘크리트 150 mm
Type - ID 데이터 - 단가: 0; 유형 마크: S4; 유형 이름: (복합)SL111(150_S4)+A1-14-03A_철콘+도막방수
Type - 그래픽 - 거친 축척 채우기 색상: 0
Type - 기타 - 내화구조여부: yes; 카테고리: 바닥; 주요구조부여부: yes; KBIMS-부위코드: E251; 조달청표준공사코드: AD+AMA31+AHJ112400000+AHC10091A+AGA133600000; 패밀리 이름: 바닥
Type - 시공 - 기능: 내부; 기본 두께: 240 mm
Type - 재료 및 마감재 - 구조 재료: KBIMS-콘크리트
Type - 해석 특성 - 거칠기: 1; 열 저항(R): 0.168403; 열 전달 계수(U): 5.93812 kg/K/s3; 열 질량: 300.585; 흡수율: 9290.3
Type - Pset_SlabCommon - IsExternal: no; ThermalTransmittance: 5.93812 kg/K/s3
Pset_QuantityTakeOff - Reference: (복합)SL111(150_S4)+A1-14-03A_철콘+도막방수; sets with these values: 2
Pset_SlabCommon - LoadBearing: yes; PitchAngle: 0 deg; Reference: (복합)SL111(150_S4)+A1-14-03A_철콘+도막방수
BaseQuantities - Width: 240 mm
공정 - 생성 공정: 새 구성
구속조건 - 매스와 관련됨: no; 룸 경계: yes; 레벨: 지상 10층; 레벨로부터 높이 간격띄우기: 80 mm
구조 - 구조: yes; 보강 철근 피복 - 다른 면: 보강 철근 피복 1 <25 mm>; 보강 철근 피복 - 상단 면: 보강 철근 피복 1 <25 mm>; 보강 철근 피복 - 하단 면: 보강 철근 피복 1 <25 mm>
기타 - 패밀리: 바닥; 유형: (복합)SL111(150_S4)+A1-14-03A_철콘+도막방수; 유형 ID: 7726383; 패밀리 및 유형: 바닥: (복합)SL111(150_S4)+A1-14-03A_철콘+도막방수
치수 - 두께: 240 mm; 상단 기준 레벨: 38480 mm; 상단 기준 레벨 측량: 38480 mm; 상단 코어의 입면도: 38440 mm; 코어 두께: 200 mm; 하단 기준 레벨: 38240 mm; 하단 기준 레벨 측량: 38240 mm; 하단 코어의 입면도: 38240 mm
Name (바닥:(복합)SL111(150_S4)+A1-14-03A_철콘+도막방수:...) | GrossArea (m2) = NetArea (m2) = 면적 (m2) | GrossVolume (m3) = NetVolume (m3) = 체적 (m3) | Perimeter (mm) = 둘레 (mm) | 연관 있음
3172343 | 18.15 | 4.356 | 17600 | yes
7726456 | 11.44 | 2.74561 | 14000 | no

# IfcSlab: 바닥:(복합)SL111(150_S4)+A1-15-01B_철콘+화강석, 바닥:(복합)SL111(150_S4)+A1-15-01B_철콘+화강석:3172329
In: 지상 10층
Type - PredefinedType: FLOOR; Material: SL312-화강석물갈기 바닥 (바탕30mm, 마감30mm) 80 mm, KBIMS-콘크리트 150 mm
Type - ID 데이터 - 단가: 0; 유형 마크: S4; 유형 이름: (복합)SL111(150_S4)+A1-15-01B_철콘+화강석
Type - 그래픽 - 거친 축척 채우기 색상: 0
Type - 기타 - 내화구조여부: yes; 카테고리: 바닥; 주요구조부여부: yes; KBIMS-부위코드: E251; 조달청표준공사코드: AD+AMB3211B; 패밀리 이름: 바닥
Type - 시공 - 기능: 내부; 기본 두께: 230 mm
Type - 재료 및 마감재 - 구조 재료: KBIMS-콘크리트
Type - 해석 특성 - 거칠기: 1; 열 저항(R): 0.166326; 열 전달 계수(U): 6.01229 kg/K/s3; 열 질량: 408.681; 흡수율: 9290.3
Type - Pset_SlabCommon - IsExternal: no; ThermalTransmittance: 6.01229 kg/K/s3
Pset_QuantityTakeOff - Reference: (복합)SL111(150_S4)+A1-15-01B_철콘+화강석; sets with these values: 2
Pset_SlabCommon - LoadBearing: yes; PitchAngle: 0 deg; Reference: (복합)SL111(150_S4)+A1-15-01B_철콘+화강석
BaseQuantities - GrossArea: 10.2599 m2; NetArea: 10.2599 m2; GrossVolume: 2.35978 m3; NetVolume: 2.35978 m3; Perimeter: 15000 mm; Width: 230 mm
ID 데이터 - 연관 있음: yes
공정 - 생성 공정: 새 구성
구속조건 - 매스와 관련됨: no; 룸 경계: yes; 레벨: 지상 10층; 레벨로부터 높이 간격띄우기: 80 mm
구조 - 구조: yes; 보강 철근 피복 - 다른 면: 보강 철근 피복 1 <25 mm>; 보강 철근 피복 - 상단 면: 보강 철근 피복 1 <25 mm>; 보강 철근 피복 - 하단 면: 보강 철근 피복 1 <25 mm>
기타 - 패밀리: 바닥; 유형: (복합)SL111(150_S4)+A1-15-01B_철콘+화강석; 유형 ID: 7726581; 패밀리 및 유형: 바닥: (복합)SL111(150_S4)+A1-15-01B_철콘+화강석
치수 - 두께: 230 mm; 둘레: 15000 mm; 면적: 10.2599 m2; 상단 기준 레벨: 38480 mm; 상단 기준 레벨 측량: 38480 mm; 상단 코어의 입면도: 38400 mm; 체적: 2.35978 m3; 코어 두께: 150 mm; 하단 기준 레벨: 38250 mm; 하단 기준 레벨 측량: 38250 mm; 하단 코어의 입면도: 38250 mm

# IfcSlab: 바닥:A1-12-06A-알칼리방지용방수, 시멘트모르타르(보호용), 자동수평 모르타르, 우레탄페인트 (40mm) (2)
In: 옥탑층
Type - PredefinedType: FLOOR; Material: SL661-우레탄페인트 바닥 3 mm, SL595-자동수평모르타르 바닥 7 mm, SL553-보호모르타르 바닥 (콘크리트면) 30mm 29 mm, SL549-알칼리방지용방수 바닥 1 mm
Type - ID 데이터 - 단가: 0; 유형 이름: A1-12-06A-알칼리방지용방수, 시멘트모르타르(보호용), 자동수평 모르타르, 우레탄페인트 (40mm)
Type - 그래픽 - 거친 축척 채우기 색상: 0
Type - 기타 - 카테고리: 바닥; KBIMS-부위코드: E25; 불연성재료: 불연재료; 조달청표준공사코드: AND011+ANJ210503A+AHJ112400000+AHK110C; 패밀리 이름: 바닥
Type - 시공 - 기능: 내부; 기본 두께: 40 mm
Type - 해석 특성 - 거칠기: 1; 흡수율: 30.48
Type - Pset_SlabCommon - IsExternal: no
Pset_QuantityTakeOff - Reference: A1-12-06A-알칼리방지용방수, 시멘트모르타르(보호용), 자동수평 모르타르, 우레탄페인트 (40mm); sets with these values: 2
Pset_SlabCommon - PitchAngle: 0 deg; LoadBearing: no; Reference: A1-12-06A-알칼리방지용방수, 시멘트모르타르(보호용), 자동수평 모르타르, 우레탄페인트 (40mm)
ID 데이터 - 연관 있음: no
공정 - 생성 공정: 새 구성
구속조건 - 매스와 관련됨: no; 룸 경계: no; 레벨로부터 높이 간격띄우기: 40 mm
구조 - 구조: no
기타 - 패밀리: 바닥; 유형: A1-12-06A-알칼리방지용방수, 시멘트모르타르(보호용), 자동수평 모르타르, 우레탄페인트 (40mm); 유형 ID: 6843289; 패밀리 및 유형: 바닥: A1-12-06A-알칼리방지용방수, 시멘트모르타르(보호용), 자동수평 모르타르, 우레탄페인트 (40mm)
치수 - 두께: 40 mm
Name (바닥:A1-12-06A-알칼리방지용방수, 시멘트모르타르(보호용), 자동수평 모르타르, 우레탄페인트 (40mm):...) | NetArea (m2) = 면적 (m2) | NetVolume (m3) = 체적 (m3) | 레벨 | 둘레 (mm) | 상단 기준 레벨 (mm) | 하단 기준 레벨 (mm)
2994802 | 83.0926 | 3.3237 | 지붕층 | 45403.7 | 47440 | 47400 | BaseQuantities - GrossArea: 83.0926 m2; GrossVolume: 3.3237 m3; Perimeter: 45403.7 mm; Width: 40 mm
2994883 | 1045.41 | 41.8163 | 옥탑층 | 186724 | 43440 | 43400 | 슬래브 모양 편집 - 곡선 모서리 조건: 0

# IfcSlab: 바닥:A1-12-09B-쇠흙손마감, 와이어매쉬(#8 150x150), 무근콘크리트, 에폭시페인트 (100mm) (2)
Type - PredefinedType: FLOOR; Material: SL671-에폭시페인트 바닥 (내산, 로울러칠, 3회) 3 mm, SL582-무근콘크리트 바닥 97mm 95 mm, SL789-와이어매쉬 #8 150x150 1 mm, SL555-쇠흙손마감 바닥 (콘크리트면) 1 mm
Type - ID 데이터 - 단가: 0; 유형 이름: A1-12-09B-쇠흙손마감, 와이어매쉬(#8 150x150), 무근콘크리트, 에폭시페인트 (100mm)
Type - 그래픽 - 거친 축척 채우기 색상: 0
Type - 기타 - 카테고리: 바닥; KBIMS-부위코드: E25; 불연성재료: 불연재료; 조달청표준공사코드: ANI000012030+ADF102100000+AJM4B+AGA441100000; 패밀리 이름: 바닥
Type - 시공 - 기능: 내부; 기본 두께: 100 mm
Type - 해석 특성 - 거칠기: 1; 열 저항(R): 0.0908222; 열 전달 계수(U): 11.0105 kg/K/s3; 열 질량: 143.554; 흡수율: 30.48
Type - Pset_SlabCommon - IsExternal: no; ThermalTransmittance: 11.0105 kg/K/s3
Pset_QuantityTakeOff - Reference: A1-12-09B-쇠흙손마감, 와이어매쉬(#8 150x150), 무근콘크리트, 에폭시페인트 (100mm); sets with these values: 2
Pset_SlabCommon - PitchAngle: 0 deg; LoadBearing: no; Reference: A1-12-09B-쇠흙손마감, 와이어매쉬(#8 150x150), 무근콘크리트, 에폭시페인트 (100mm)
BaseQuantities - Width: 100 mm
ID 데이터 - 연관 있음: no
공정 - 생성 공정: 새 구성
구속조건 - 매스와 관련됨: no; 룸 경계: no; 레벨로부터 높이 간격띄우기: 100 mm
구조 - 구조: no
기타 - 패밀리: 바닥; 유형: A1-12-09B-쇠흙손마감, 와이어매쉬(#8 150x150), 무근콘크리트, 에폭시페인트 (100mm); 유형 ID: 6843374; 패밀리 및 유형: 바닥: A1-12-09B-쇠흙손마감, 와이어매쉬(#8 150x150), 무근콘크리트, 에폭시페인트 (100mm)
치수 - 두께: 100 mm
Name (바닥:A1-12-09B-쇠흙손마감, 와이어매쉬(#8 150x150), 무근콘크리트, 에폭시페인트 (100mm):...) | In | GrossArea (m2) = NetArea (m2) = 면적 (m2) | GrossVolume (m3) = NetVolume (m3) = 체적 (m3) | Perimeter (mm) = 둘레 (mm) | 레벨 | 상단 기준 레벨 (mm) | 하단 기준 레벨 (mm)
2825928 | 지하2층 | 736.5 | 73.65 | 133880 | 지하2층 | -10000 | -10100
2826854 | 지하1층 | 1051.94 | 105.194 | 173574 | 지하1층 | -6000 | -6100

# IfcSlab: 바닥:A1-12-13B-시멘트 액체방수(2차), 와이어매쉬(#8 150x150), 무근콘크리트, 시멘트모르타르(고름용), 우레탄페인트 (160mm) (6)
Type - PredefinedType: FLOOR; Material: SL661-우레탄페인트 바닥 1 mm, SL552-바탕고르기(시멘트모르타르) 바닥 30mm 29 mm, SL582-무근콘크리트 바닥 100mm 99 mm, SL789-와이어매쉬 #8 150x150 1 mm, SL531-시멘트액체방수 바닥 (2차 30mm) 30 mm
Type - ID 데이터 - 단가: 0; 유형 이름: A1-12-13B-시멘트 액체방수(2차), 와이어매쉬(#8 150x150), 무근콘크리트, 시멘트모르타르(고름용), 우레탄페인트 (160mm)
Type - 그래픽 - 거친 축척 채우기 색상: 0
Type - 기타 - 카테고리: 바닥; KBIMS-부위코드: E25; 불연성재료: 불연재료; 조달청표준공사코드: AND011+AGA310500000+ADF102100000+AJM4B+AHI0004E; 패밀리 이름: 바닥
Type - 시공 - 기능: 내부; 기본 두께: 160 mm
Type - 해석 특성 - 거칠기: 1; 흡수율: 30.48
Type - Pset_SlabCommon - IsExternal: no
Pset_QuantityTakeOff - Reference: A1-12-13B-시멘트 액체방수(2차), 와이어매쉬(#8 150x150), 무근콘크리트, 시멘트모르타르(고름용), 우레탄페인트 (160mm); sets with these values: 2
Pset_SlabCommon - PitchAngle: 0 deg; LoadBearing: no; Reference: A1-12-13B-시멘트 액체방수(2차), 와이어매쉬(#8 150x150), 무근콘크리트, 시멘트모르타르(고름용), 우레탄페인트 (160mm)
ID 데이터 - 연관 있음: no
공정 - 생성 공정: 새 구성
구속조건 - 매스와 관련됨: no; 룸 경계: no; 레벨로부터 높이 간격띄우기: 160 mm
구조 - 구조: no
기타 - 패밀리: 바닥; 유형: A1-12-13B-시멘트 액체방수(2차), 와이어매쉬(#8 150x150), 무근콘크리트, 시멘트모르타르(고름용), 우레탄페인트 (160mm); 유형 ID: 6843431; 패밀리 및 유형: 바닥: A1-12-13B-시멘트 액체방수(2차), 와이어매쉬(#8 150x150), 무근콘크리트, 시멘트모르타르(고름용), 우레탄페인트 (160mm)
치수 - 두께: 160 mm
Name (바닥:A1-12-13B-시멘트 액체방수(2차), 와이어매쉬(#8 150x150), 무근콘크리트, 시멘트모르타르(고름용), 우레탄페인트 (160mm):...) | In | GrossArea (m2) | NetArea (m2) = 면적 (m2) | GrossVolume (m3) | NetVolume (m3) = 체적 (m3) | Perimeter (mm) | Width (mm) | 레벨 | 둘레 (mm) | 상단 기준 레벨 (mm) | 하단 기준 레벨 (mm)
2826415 | 지하2층 | 19.1631 | 19.1558 | 3.06609 | 3.06543 | 18762.1 | 160 | 지하2층 | 18762.1 | -9940 | -10100
2826904 | 지하1층 | 19.1631 | 19.1558 | 3.06609 | 3.06543 | 18762.1 | 160 | 지하1층 | 18762.1 | -5940 | -6100
2826915 | 지하1층 | 14.85 | 14.85 | 2.376 | 2.376 | 16400 | 160 | 지하1층 | 16400 | -5940 | -6100
3095790 | 지하2층 | 344.695 | 344.695 | 55.1512 | 55.1512 | 78607.8 | 160 | PIT | 78607.8 | -11740 | -11900
3696224 | 지하2층 | 99.6197 | 99.6206 | 15.9392 | 15.9393 | 62657.8 | 160 | PIT | 53154.3 | -11740 | -11900
3696456 | 지하1층 |  | 72.8833 |  | 11.6613 |  |  | 지하1층 | 37704.8 | -5940 | -6100

# IfcSlab: 바닥:A1-14-03A-시멘트모르타르(고름용), 도막방수, 시멘트모르타르(보호용), 자기질타일 (90mm) (18)
Type - PredefinedType: FLOOR; Material: SL351-자기질타일 바닥 (바탕32mm, 압착8mm) 40 mm, SL553-보호모르타르 바닥 (콘크리트면) 30mm 30 mm, SL521-도막방수 바닥 (비노출) 3mm 3 mm, SL551-시멘트모르타르 미장 바닥 17mm 17 mm
Type - ID 데이터 - 단가: 0; 유형 이름: A1-14-03A-시멘트모르타르(고름용), 도막방수, 시멘트모르타르(보호용), 자기질타일 (90mm)
Type - 그래픽 - 거친 축척 채우기 색상: 0
Type - 기타 - 카테고리: 바닥; KBIMS-부위코드: E25; 불연성재료: 불연재료; 조달청표준공사코드: AMA31+AHJ112400000+AHC10091A+AGA133600000; 패밀리 이름: 바닥
Type - 시공 - 기능: 내부; 기본 두께: 90 mm
Type - 해석 특성 - 거칠기: 1; 열 저항(R): 0.025; 열 전달 계수(U): 40 kg/K/s3; 열 질량: 73.92; 흡수율: 30.48
Type - Pset_SlabCommon - IsExternal: no; ThermalTransmittance: 40 kg/K/s3
Pset_QuantityTakeOff - Reference: A1-14-03A-시멘트모르타르(고름용), 도막방수, 시멘트모르타르(보호용), 자기질타일 (90mm); sets with these values: 2
Pset_SlabCommon - PitchAngle: 0 deg; LoadBearing: no; Reference: A1-14-03A-시멘트모르타르(고름용), 도막방수, 시멘트모르타르(보호용), 자기질타일 (90mm)
BaseQuantities - Width: 90 mm
ID 데이터 - 연관 있음: no; 해설: A
공정 - 생성 공정: 새 구성
구속조건 - 매스와 관련됨: no; 룸 경계: no
구조 - 구조: no
기타 - 패밀리: 바닥; 유형: A1-14-03A-시멘트모르타르(고름용), 도막방수, 시멘트모르타르(보호용), 자기질타일 (90mm); 유형 ID: 6843582; 패밀리 및 유형: 바닥: A1-14-03A-시멘트모르타르(고름용), 도막방수, 시멘트모르타르(보호용), 자기질타일 (90mm)
치수 - 두께: 90 mm
Name (바닥:A1-14-03A-시멘트모르타르(고름용), 도막방수, 시멘트모르타르(보호용), 자기질타일 (90mm):...) | In | GrossArea (m2) = NetArea (m2) = 면적 (m2) | GrossVolume (m3) = NetVolume (m3) = 체적 (m3) | Perimeter (mm) = 둘레 (mm) | 레벨 | 레벨로부터 높이 간격띄우기 (mm) | 상단 기준 레벨 (mm) | 하단 기준 레벨 (mm)
3146174 | 지상 1층 | 17.6 | 1.584 | 17400 | 지상 1층 | -510 | -510 | -600
7621809 | 지상 1층 | 11.44 | 1.0296 | 14000 | 지상 1층 | -510 | -510 | -600
7622043 | 지상 2층 | 17.6 | 1.584 | 17400 | 지상 2층 | 40 | 4840 | 4750
7622050 | 지상 2층 | 11.4401 | 1.02961 | 14000 | 지상 2층 | 40 | 4840 | 4750
7622070 | 지상 3층 | 17.6 | 1.584 | 17400 | 지상 3층 | 40 | 9340 | 9250
7622077 | 지상 3층 | 11.4401 | 1.02961 | 14000 | 지상 3층 | 40 | 9340 | 9250
7622097 | 지상 4층 | 17.6 | 1.584 | 17400 | 지상 4층 | 40 | 13440 | 13350
7622104 | 지상 4층 | 11.4401 | 1.02961 | 14000 | 지상 4층 | 40 | 13440 | 13350
7622124 | 지상 5층 | 17.6 | 1.584 | 17400 | 지상 5층 | 40 | 17540 | 17450
7622131 | 지상 5층 | 11.4401 | 1.02961 | 14000 | 지상 5층 | 40 | 17540 | 17450
7622151 | 지상 6층 | 17.6 | 1.584 | 17400 | 지상 6층 | 40 | 21640 | 21550
7622158 | 지상 6층 | 11.4401 | 1.02961 | 14000 | 지상 6층 | 40 | 21640 | 21550
7622178 | 지상 7층 | 17.6 | 1.584 | 17400 | 지상 7층 | 40 | 25740 | 25650
7622185 | 지상 7층 | 11.4401 | 1.02961 | 14000 | 지상 7층 | 40 | 25740 | 25650
7622205 | 지상 8층 | 17.6 | 1.584 | 17400 | 지상 8층 | 40 | 29840 | 29750
7622212 | 지상 8층 | 11.4401 | 1.02961 | 14000 | 지상 8층 | 40 | 29840 | 29750
7622232 | 지상 9층 | 17.6 | 1.584 | 17400 | 지상 9층 | 40 | 33940 | 33850
7622239 | 지상 9층 | 11.4401 | 1.02961 | 14000 | 지상 9층 | 40 | 33940 | 33850

# IfcSlab: 바닥:A1-14-06B-테라조타일 (80mm) (71)
Type - PredefinedType: FLOOR; Material: SL341-테라조 바닥 (바탕48mm, 마감32mm) 80 mm
Type - ID 데이터 - 단가: 0; 유형 이름: A1-14-06B-테라조타일 (80mm)
Type - 그래픽 - 거친 축척 채우기 색상: 0
Type - 기타 - 카테고리: 바닥; KBIMS-부위코드: E25; 불연성재료: 불연재료; 조달청표준공사코드: AMB3032E; 패밀리 이름: 바닥
Type - 시공 - 기능: 내부; 기본 두께: 80 mm
Type - 해석 특성 - 거칠기: 1; 흡수율: 30.48
Type - Pset_SlabCommon - IsExternal: no
Pset_QuantityTakeOff - Reference: A1-14-06B-테라조타일 (80mm); sets with these values: 2
Pset_SlabCommon - PitchAngle: 0 deg; LoadBearing: no; Reference: A1-14-06B-테라조타일 (80mm)
BaseQuantities - Width: 80 mm
ID 데이터 - 연관 있음: no
공정 - 생성 공정: 새 구성
구속조건 - 매스와 관련됨: no; 룸 경계: no
구조 - 구조: no
기타 - 패밀리: 바닥; 유형: A1-14-06B-테라조타일 (80mm); 유형 ID: 6843713; 패밀리 및 유형: 바닥: A1-14-06B-테라조타일 (80mm)
치수 - 두께: 80 mm
Name (바닥:A1-14-06B-테라조타일 (80mm):...) | In | GrossArea (m2) = NetArea (m2) = 면적 (m2) | GrossVolume (m3) = NetVolume (m3) = 체적 (m3) | Perimeter (mm) = 둘레 (mm) | 레벨 | 레벨로부터 높이 간격띄우기 (mm) | 상단 기준 레벨 (mm) | 하단 기준 레벨 (mm)
2827098 | 지상 1층 | 44.8854 | 3.59083 | 29550.1 | 지상 1층 | -1420 | -1420 | -1500
2827108 | 지상 1층 | 61.7937 | 4.9435 | 40871.4 | 지상 1층 | 80 | 80 | 0
2827125 | 지상 1층 | 53.203 | 4.25624 | 34771.3 | 지상 1층 | 80 | 80 | 0
2827143 | 지상 1층 | 52.8275 | 4.2262 | 34680.1 | 지상 1층 | 80 | 80 | 0
2827151 | 지상 1층 | 47.0958 | 3.76766 | 30025 | 지상 1층 | -420 | -420 | -500
2827164 | 지상 1층 | 39.7374 | 3.17899 | 28174.9 | 지상 1층 | 80 | 80 | 0
2827179 | 지상 1층 | 67.6399 | 5.41119 | 35765 | 지상 1층 | 80 | 80 | 0
2827918 | 지상 2층 | 115.14 | 9.21116 | 48550 | 지상 2층 | 80 | 4880 | 4800
5382697 | 지상 2층 | 105.978 | 8.4782 | 42845 | 지상 2층 | 80 | 4880 | 4800
5382759 | 지상 2층 | 279.278 | 22.3423 | 74874.9 | 지상 2층 | 80 | 4880 | 4800
5382860 | 지상 2층 | 129.66 | 10.3728 | 45845 | 지상 2층 | 80 | 4880 | 4800
5382976 | 지상 2층 | 147.039 | 11.7631 | 52214.9 | 지상 2층 | 80 | 4880 | 4800
5383110 | 지상 2층 | 137.341 | 10.9873 | 50135.1 | 지상 2층 | 80 | 4880 | 4800
5399653 | 지상 3층 | 77.3025 | 6.1842 | 42420 | 지상 3층 | 80 | 9380 | 9300
5399692 | 지상 3층 | 106.803 | 8.54421 | 43095 | 지상 3층 | 80 | 9380 | 9300
5399715 | 지상 3층 | 130.799 | 10.4639 | 46075 | 지상 3층 | 80 | 9380 | 9300
5399726 | 지상 3층 | 149.862 | 11.989 | 52949.9 | 지상 3층 | 80 | 9380 | 9300
5399745 | 지상 3층 | 138.74 | 11.0992 | 50600 | 지상 3층 | 80 | 9380 | 9300
5400003 | 지상 3층 | 36.705 | 2.9364 | 26300 | 지상 3층 | 80 | 9380 | 9300
5400174 | 지상 3층 | 196.333 | 15.7067 | 59784.9 | 지상 3층 | 80 | 9380 | 9300
5400413 | 지상 4층 | 123.68 | 9.89439 | 48800 | 지상 4층 | 80 | 13480 | 13400
5400452 | 지상 4층 | 106.803 | 8.54424 | 43095.2 | 지상 4층 | 80 | 13480 | 13400
5400467 | 지상 4층 | 86.3268 | 6.90614 | 39695 | 지상 4층 | 80 | 13480 | 13400
5400475 | 지상 4층 | 130.891 | 10.4713 | 46095 | 지상 4층 | 80 | 13480 | 13400
5400486 | 지상 4층 | 149.785 | 11.9828 | 52930 | 지상 4층 | 80 | 13480 | 13400
5400505 | 지상 4층 | 138.845 | 11.1076 | 50620 | 지상 4층 | 80 | 13480 | 13400
5400567 | 지상 4층 | 196.346 | 15.7077 | 59795 | 지상 4층 | 80 | 13480 | 13400
5400985 | 지상 5층 | 123.68 | 9.89439 | 48800 | 지상 5층 | 80 | 17580 | 17500
5401024 | 지상 5층 | 106.803 | 8.54421 | 43095.1 | 지상 5층 | 80 | 17580 | 17500
5401039 | 지상 5층 | 87.1647 | 6.97317 | 39819.9 | 지상 5층 | 80 | 17580 | 17500
5401045 | 지상 5층 | 130.898 | 10.4718 | 46095 | 지상 5층 | 80 | 17580 | 17500
5401056 | 지상 5층 | 149.824 | 11.9859 | 52939.9 | 지상 5층 | 80 | 17580 | 17500
5401075 | 지상 5층 | 139.313 | 11.145 | 50210 | 지상 5층 | 80 | 17580 | 17500
5401133 | 지상 5층 | 196.471 | 15.7177 | 59895 | 지상 5층 | 80 | 17580 | 17500
5401395 | 지상 6층 | 123.68 | 9.89439 | 48800 | 지상 6층 | 80 | 21680 | 21600
5401434 | 지상 6층 | 106.803 | 8.5442 | 43095 | 지상 6층 | 80 | 21680 | 21600
5401449 | 지상 6층 | 87.1649 | 6.97319 | 39820 | 지상 6층 | 80 | 21680 | 21600
5401455 | 지상 6층 | 130.898 | 10.4718 | 46095 | 지상 6층 | 80 | 21680 | 21600
5401466 | 지상 6층 | 149.785 | 11.9828 | 52929.9 | 지상 6층 | 80 | 21680 | 21600
5401485 | 지상 6층 | 139.365 | 11.1492 | 50220 | 지상 6층 | 80 | 21680 | 21600
5401543 | 지상 6층 | 196.471 | 15.7177 | 59895 | 지상 6층 | 80 | 21680 | 21600
5401809 | 지상 7층 | 123.68 | 9.89439 | 48800 | 지상 7층 | 80 | 25780 | 25700
5401848 | 지상 7층 | 106.803 | 8.5442 | 43095 | 지상 7층 | 80 | 25780 | 25700
5401863 | 지상 7층 | 87.1649 | 6.97319 | 39820 | 지상 7층 | 80 | 25780 | 25700
5401869 | 지상 7층 | 130.898 | 10.4718 | 46095 | 지상 7층 | 80 | 25780 | 25700
5401880 | 지상 7층 | 149.785 | 11.9828 | 52929.9 | 지상 7층 | 80 | 25780 | 25700
5401899 | 지상 7층 | 139.365 | 11.1492 | 50220.1 | 지상 7층 | 80 | 25780 | 25700
5401957 | 지상 7층 | 196.471 | 15.7177 | 59895 | 지상 7층 | 80 | 25780 | 25700
5402214 | 지상 8층 | 123.94 | 9.91519 | 48600 | 지상 8층 | 80 | 29880 | 29800
5402253 | 지상 8층 | 107.372 | 8.58973 | 43095 | 지상 8층 | 80 | 29880 | 29800
5402268 | 지상 8층 | 87.1649 | 6.97319 | 39820 | 지상 8층 | 80 | 29880 | 29800
5402274 | 지상 8층 | 131.176 | 10.4941 | 46095 | 지상 8층 | 80 | 29880 | 29800
5402285 | 지상 8층 | 150.364 | 12.0291 | 52730 | 지상 8층 | 80 | 29880 | 29800
5402304 | 지상 8층 | 139.365 | 11.1492 | 50220 | 지상 8층 | 80 | 29880 | 29800
5402362 | 지상 8층 | 197.059 | 15.7647 | 59495 | 지상 8층 | 80 | 29880 | 29800
5402619 | 지상 9층 | 116.299 | 9.30395 | 48600 | 지상 9층 | 80 | 33980 | 33900
5402658 | 지상 9층 | 107.372 | 8.58977 | 43095 | 지상 9층 | 80 | 33980 | 33900
5402673 | 지상 9층 | 87.1649 | 6.97319 | 39820 | 지상 9층 | 80 | 33980 | 33900
5402679 | 지상 9층 | 131.176 | 10.4941 | 46095 | 지상 9층 | 80 | 33980 | 33900
5402690 | 지상 9층 | 150.364 | 12.0291 | 52730 | 지상 9층 | 80 | 33980 | 33900
5402709 | 지상 9층 | 139.365 | 11.1492 | 50220 | 지상 9층 | 80 | 33980 | 33900
5402767 | 지상 9층 | 197.059 | 15.7647 | 59495 | 지상 9층 | 80 | 33980 | 33900
5458177 | 지상 1층 | 50.1504 | 4.01203 | 34119.9 | 지상 1층 | 80 | 80 | 0
5458192 | 지상 1층 | 52.3721 | 4.18977 | 34646.2 | 지상 1층 | 80 | 80 | 0
5458225 | 지상 1층 | 53.6382 | 4.29106 | 34645 | 지상 1층 | 80 | 80 | 0
5458236 | 지상 1층 | 52.2997 | 4.18398 | 34594.9 | 지상 1층 | 80 | 80 | 0
5458270 | 지상 1층 | 65.4921 | 5.23936 | 35345 | 지상 1층 | 80 | 80 | 0
5458292 | 지상 1층 | 40.6778 | 3.25422 | 28225 | 지상 1층 | 80 | 80 | 0
5458303 | 지상 1층 | 40.5253 | 3.24203 | 28350.1 | 지상 1층 | 80 | 80 | 0
5458322 | 지상 1층 | 42.9262 | 3.4341 | 29024.9 | 지상 1층 | -1420 | -1420 | -1500
5921481 | 지상 3층 | 86.3268 | 6.90614 | 39695 | 지상 3층 | 80 | 9380 | 9300

# IfcSlab: 바닥:A1-15-01B-화강석(물갈기) (80mm) (22)
Type - PredefinedType: FLOOR; Material: SL312-화강석물갈기 바닥 (바탕30mm, 마감30mm) 80 mm
Type - ID 데이터 - 단가: 0; 유형 이름: A1-15-01B-화강석(물갈기) (80mm)
Type - 그래픽 - 거친 축척 채우기 색상: 0
Type - 기타 - 카테고리: 바닥; KBIMS-부위코드: E25; 불연성재료: 불연재료; 조달청표준공사코드: AMB3211B; 패밀리 이름: 바닥
Type - 시공 - 기능: 내부; 기본 두께: 80 mm
Type - 해석 특성 - 거칠기: 1; 열 저항(R): 0.0229226; 열 전달 계수(U): 43.625 kg/K/s3; 열 질량: 182.016; 흡수율: 30.48
Type - Pset_SlabCommon - IsExternal: no; ThermalTransmittance: 43.625 kg/K/s3
Pset_QuantityTakeOff - Reference: A1-15-01B-화강석(물갈기) (80mm); sets with these values: 2
Pset_SlabCommon - LoadBearing: no; Reference: A1-15-01B-화강석(물갈기) (80mm)
ID 데이터 - 연관 있음: no
공정 - 생성 공정: 새 구성
구속조건 - 매스와 관련됨: no; 룸 경계: no
구조 - 구조: no
기타 - 패밀리: 바닥; 유형: A1-15-01B-화강석(물갈기) (80mm); 유형 ID: 6843992; 패밀리 및 유형: 바닥: A1-15-01B-화강석(물갈기) (80mm)
치수 - 두께: 80 mm
Name (바닥:A1-15-01B-화강석(물갈기) (80mm):...) | In | PitchAngle (deg) | GrossArea (m2) = NetArea (m2) = 면적 (m2) | GrossVolume (m3) | NetVolume (m3) = 체적 (m3) | Perimeter (mm) | Width (mm) | 레벨 | 레벨로부터 높이 간격띄우기 (mm) | 하단 기준 레벨 (mm) | 둘레 (mm) | 상단 기준 레벨 (mm)
2827602 | 지상 1층 | 0 | 7.12743 | 0.570194 | 0.570194 | 11148.6 | 80 | 지상 1층 | 80 | 0 | 11148.6 | 80
2827622 | 지상 1층 | 0 | 7.52886 | 0.602309 | 0.602309 | 11023.1 | 80 | 지상 1층 | -420 | -500 | 11023.1 | -420 | ID 데이터 - 해설: A
2827629 | 지상 1층 | 0 | 5.57119 | 0.445695 | 0.445695 | 9456.59 | 80 | 지상 1층 | -420 | -500 | 9456.59 | -420 | ID 데이터 - 해설: A
2827750 | 지상 1층 | 0 | 19.8751 | 1.59001 | 1.59001 | 20900.1 | 80 | 지상 1층 | 80 | 0 | 20900.1 | 80 | ID 데이터 - 해설: A
2827757 | 지상 1층 | 0 | 7.3 | 0.584 | 0.584 | 13000 | 80 | 지상 1층 | -470 | -550 | 13000 | -470 | ID 데이터 - 해설: A
2827763 | 지상 1층 | 0 | 18.8498 | 1.50798 | 1.50798 | 20603.7 | 80 | 지상 1층 | 80 | 0 | 20603.7 | 80 | ID 데이터 - 해설: A
2827770 | 지상 1층 | 0 | 9.95512 | 0.79641 | 0.79641 | 12966.3 | 80 | 지상 1층 | 80 | 0 | 12966.3 | 80 | ID 데이터 - 해설: A
2827777 | 지상 1층 | 0 | 5.87817 | 0.470254 | 0.470254 | 9707.95 | 80 | 지상 1층 | 80 | 0 | 9707.95 | 80 | ID 데이터 - 해설: A
2828169 | 지상 2층 | 0 | 7.12743 | 0.570194 | 0.570194 | 11148.6 | 80 | 지상 2층 | 80 | 4800 | 11148.6 | 4880
5324476 | 지상 1층 | 6.2773 | 10.0603 | 0.809676 | 0.804822 | 14060.3 | 80.4825 | 지상 1층 | -470 |  | 14000
5342761 | 지상 1층 | 0 | 58.7452 | 4.69962 | 4.69962 | 31094.9 | 80 | 지상 1층 | 80 | 0 | 31094.9 | 80
5399660 | 지상 3층 | 0 | 7.12357 | 0.569885 | 0.569885 | 11144.9 | 80 | 지상 3층 | 80 | 9300 | 11144.9 | 9380
5399674 | 지상 3층 | 0 | 99.6099 | 7.9688 | 7.9688 | 92696.7 | 80 | 지상 3층 | 80 | 9300 | 92696.7 | 9380
5400420 | 지상 4층 | 0 | 7.12357 | 0.569885 | 0.569885 | 11144.9 | 80 | 지상 4층 | 80 | 13400 | 11144.9 | 13480
5400992 | 지상 5층 | 0 | 7.12357 | 0.569885 | 0.569885 | 11144.9 | 80 | 지상 5층 | 80 | 17500 | 11144.9 | 17580
5401402 | 지상 6층 | 0 | 7.12357 | 0.569885 | 0.569885 | 11144.9 | 80 | 지상 6층 | 80 | 21600 | 11144.9 | 21680
5401416 | 지상 6층 | 0 | 92.4343 | 7.39474 | 7.39474 | 86844.6 | 80 | 지상 6층 | 80 | 21600 | 86844.6 | 21680
5401816 | 지상 7층 | 0 | 7.12357 | 0.569885 | 0.569885 | 11144.9 | 80 | 지상 7층 | 80 | 25700 | 11144.9 | 25780
5402221 | 지상 8층 | 0 | 7.12357 | 0.569885 | 0.569885 | 11144.9 | 80 | 지상 8층 | 80 | 29800 | 11144.9 | 29880
5402626 | 지상 9층 | 0 | 7.12357 | 0.569885 | 0.569885 | 11144.9 | 80 | 지상 9층 | 80 | 33900 | 11144.9 | 33980
5458332 | 지상 1층 | 0 | 28.2252 | 2.25802 | 2.25802 | 21694.9 | 80 | 지상 1층 | 80 | 0 | 21694.9 | 80 | ID 데이터 - 해설: A
8042868 | 지상 1층 | 0 | 41.2589 | 3.30071 | 3.30071 | 38517.9 | 80 | 지상 1층 | 80 | 0 | 38517.9 | 80 | ID 데이터 - 해설: A

# IfcSlab: 바닥:A1-15-09B-쇠흙손마감, 침투성방수(2차), 시멘트모르타르(보호용), 와이어매쉬(#8 150x150), 무근콘크리트, 대리석(물갈기) (200mm) (4)
Type - PredefinedType: FLOOR; Material: SL322-대리석물갈기 바닥 (바탕60mm, 마감20mm) 80 mm, SL582-무근콘크리트 바닥 100mm 99 mm, SL789-와이어매쉬 #8 150x150 1 mm, SL553-보호모르타르 바닥 20mm 18 mm, SL541-침투성방수 바닥 1 mm, SL555-쇠흙손마감 바닥 (콘크리트면) 1 mm
Type - ID 데이터 - 단가: 0; 유형 이름: A1-15-09B-쇠흙손마감, 침투성방수(2차), 시멘트모르타르(보호용), 와이어매쉬(#8 150x150), 무근콘크리트, 대리석(물갈기) (200mm)
Type - 그래픽 - 거친 축척 채우기 색상: 0
Type - 기타 - 카테고리: 바닥; KBIMS-부위코드: E25; 불연성재료: 불연재료; 조달청표준공사코드: AMB322D+ADF102100000+AJM4B+AHJ111201000+AHD11+AGA441100000; 패밀리 이름: 바닥
Type - 시공 - 기능: 내부; 기본 두께: 200 mm
Type - 해석 특성 - 거칠기: 1; 열 저항(R): 0.0275862; 열 전달 계수(U): 36.25 kg/K/s3; 열 질량: 184.8; 흡수율: 30.48
Type - Pset_SlabCommon - IsExternal: no; ThermalTransmittance: 36.25 kg/K/s3
Pset_QuantityTakeOff - Reference: A1-15-09B-쇠흙손마감, 침투성방수(2차), 시멘트모르타르(보호용), 와이어매쉬(#8 150x150), 무근콘크리트, 대리석(물갈기) (200mm); sets with these values: 2
Pset_SlabCommon - PitchAngle: 0 deg; LoadBearing: no; Reference: A1-15-09B-쇠흙손마감, 침투성방수(2차), 시멘트모르타르(보호용), 와이어매쉬(#8 150x150), 무근콘크리트, 대리석(물갈기) (200mm)
BaseQuantities - Width: 200 mm
ID 데이터 - 연관 있음: no
공정 - 생성 공정: 새 구성
구속조건 - 매스와 관련됨: no; 룸 경계: no; 레벨로부터 높이 간격띄우기: 200 mm
구조 - 구조: no
기타 - 패밀리: 바닥; 유형: A1-15-09B-쇠흙손마감, 침투성방수(2차), 시멘트모르타르(보호용), 와이어매쉬(#8 150x150), 무근콘크리트, 대리석(물갈기) (200mm); 유형 ID: 6844367; 패밀리 및 유형: 바닥: A1-15-09B-쇠흙손마감, 침투성방수(2차), 시멘트모르타르(보호용), 와이어매쉬(#8 150x150), 무근콘크리트, 대리석(물갈기) (200mm)
치수 - 두께: 200 mm
Name (바닥:A1-15-09B-쇠흙손마감, 침투성방수(2차), 시멘트모르타르(보호용), 와이어매쉬(#8 150x150), 무근콘크리트, 대리석(물갈기) (200mm):...) | In | GrossArea (m2) = NetArea (m2) = 면적 (m2) | GrossVolume (m3) = NetVolume (m3) = 체적 (m3) | Perimeter (mm) = 둘레 (mm) | 레벨 | 상단 기준 레벨 (mm) | 하단 기준 레벨 (mm)
2826268 | 지하2층 | 14.3102 | 2.86203 | 16203.7 | 지하2층 | -9900 | -10100
2826283 | 지하2층 | 7.43833 | 1.48767 | 11603.7 | 지하2층 | -9900 | -10100
2826869 | 지하1층 | 15.9931 | 3.19861 | 17880.9 | 지하1층 | -5900 | -6100
2826893 | 지하1층 | 7.24078 | 1.44816 | 14575.4 | 지하1층 | -5900 | -6100

# IfcSlab: 바닥:A1-15-09B-쇠흙손마감, 침투성방수(2차), 시멘트모르타르(보호용), 와이어매쉬(#8 150x150), 무근콘크리트, 대리석(물갈기) (200mm), 바닥:A1-15-09B-쇠흙손마감, 침투성방수(2차), 시멘트모르타르(보호용), 와이어매쉬(#8 150x150), 무근콘크리트, 대리석(물갈기) (200mm):2826259
In: 지하2층
Type - PredefinedType: FLOOR
Type - ID 데이터 - 단가: 0; 유형 이름: A1-15-09B-쇠흙손마감, 침투성방수(2차), 시멘트모르타르(보호용), 와이어매쉬(#8 150x150), 무근콘크리트, 대리석(물갈기) (200mm)
Type - 그래픽 - 거친 축척 채우기 색상: 0
Type - 기타 - 카테고리: 바닥; KBIMS-부위코드: E25; 불연성재료: 불연재료; 조달청표준공사코드: AMB322D+ADF102100000+AJM4B+AHJ111201000+AHD11+AGA441100000; 패밀리 이름: 바닥
Type - 시공 - 기능: 내부; 기본 두께: 200 mm
Type - 해석 특성 - 거칠기: 1; 열 저항(R): 0.0275862; 열 전달 계수(U): 36.25 kg/K/s3; 열 질량: 184.8; 흡수율: 30.48
Type - Pset_SlabCommon - IsExternal: no; ThermalTransmittance: 36.25 kg/K/s3
Material: SL322-대리석물갈기 바닥 (바탕60mm, 마감20mm), SL582-무근콘크리트 바닥 100mm, SL789-와이어매쉬 #8 150x150, SL553-보호모르타르 바닥 20mm, SL541-침투성방수 바닥, SL555-쇠흙손마감 바닥 (콘크리트면)
Pset_QuantityTakeOff - Reference: A1-15-09B-쇠흙손마감, 침투성방수(2차), 시멘트모르타르(보호용), 와이어매쉬(#8 150x150), 무근콘크리트, 대리석(물갈기) (200mm); sets with these values: 2
Pset_SlabCommon - PitchAngle: 0 deg; LoadBearing: no; Reference: A1-15-09B-쇠흙손마감, 침투성방수(2차), 시멘트모르타르(보호용), 와이어매쉬(#8 150x150), 무근콘크리트, 대리석(물갈기) (200mm)
BaseQuantities - NetArea: 16.1312 m2; NetVolume: 3.22575 m3
ID 데이터 - 연관 있음: no
공정 - 생성 공정: 새 구성
구속조건 - 레벨: 지하2층; 매스와 관련됨: no; 룸 경계: no; 레벨로부터 높이 간격띄우기: 200 mm
구조 - 구조: no
기타 - 패밀리: 바닥; 유형: A1-15-09B-쇠흙손마감, 침투성방수(2차), 시멘트모르타르(보호용), 와이어매쉬(#8 150x150), 무근콘크리트, 대리석(물갈기) (200mm); 유형 ID: 6844367; 패밀리 및 유형: 바닥: A1-15-09B-쇠흙손마감, 침투성방수(2차), 시멘트모르타르(보호용), 와이어매쉬(#8 150x150), 무근콘크리트, 대리석(물갈기) (200mm)
치수 - 두께: 200 mm; 둘레: 17913.7 mm; 면적: 16.1312 m2; 상단 기준 레벨: -9900 mm; 체적: 3.22575 m3; 하단 기준 레벨: -10100 mm

# IfcSlab: 바닥:SL111-철근콘크리트구조 바닥 150mm_S1 (23)
Type - PredefinedType: FLOOR; Material: KBIMS-콘크리트 150 mm
Type - ID 데이터 - 단가: 0; 유형 마크: S1; 유형 이름: SL111-철근콘크리트구조 바닥 150mm_S1
Type - 그래픽 - 거친 축척 채우기 색상: 0
Type - 기타 - 내화구조여부: yes; 카테고리: 바닥; 주요구조부여부: yes; KBIMS-부위코드: E251; 조달청표준공사코드: AD; 패밀리 이름: 바닥
Type - 시공 - 기능: 내부; 기본 두께: 150 mm
Type - 재료 및 마감재 - 구조 재료: KBIMS-콘크리트
Type - 해석 특성 - 거칠기: 1; 열 저항(R): 0.143403; 열 전달 계수(U): 6.97333 kg/K/s3; 열 질량: 226.665; 흡수율: 9290.3
Type - Pset_SlabCommon - IsExternal: no; ThermalTransmittance: 6.97333 kg/K/s3
Pset_QuantityTakeOff - Reference: SL111-철근콘크리트구조 바닥 150mm_S1; sets with these values: 2
Pset_SlabCommon - LoadBearing: yes; PitchAngle: 0 deg; Reference: SL111-철근콘크리트구조 바닥 150mm_S1
BaseQuantities - Width: 150 mm
공정 - 생성 공정: 새 구성
구속조건 - 매스와 관련됨: no; 룸 경계: yes
구조 - 구조: yes; 보강 철근 피복 - 다른 면: 보강 철근 피복 1 <25 mm>; 보강 철근 피복 - 상단 면: 보강 철근 피복 1 <25 mm>; 보강 철근 피복 - 하단 면: 보강 철근 피복 1 <25 mm>
기타 - 패밀리: 바닥; 유형: SL111-철근콘크리트구조 바닥 150mm_S1; 유형 ID: 7622584; 패밀리 및 유형: 바닥: SL111-철근콘크리트구조 바닥 150mm_S1
치수 - 두께: 150 mm; 코어 두께: 150 mm
Name (바닥:SL111-철근콘크리트구조 바닥 150mm_S1:...) | In | GrossArea (m2) = NetArea (m2) = 면적 (m2) | GrossVolume (m3) | NetVolume (m3) = 체적 (m3) | Perimeter (mm) = 둘레 (mm) | 연관 있음 | 레벨로부터 높이 간격띄우기 (mm) | 레벨 | 상단 기준 레벨 (mm) = 상단 기준 레벨 측량 (mm) = 상단 코어의 입면도 (mm) | 하단 기준 레벨 (mm) = 하단 기준 레벨 측량 (mm) = 하단 코어의 입면도 (mm)
2699028 | 지하1층 | 90.09 | 13.5135 | 13.5135 | 38000 | yes | 0 | 지하1층 | -6100 | -6250
2699038 | 지하1층 | 24.9274 | 3.73912 | 3.73912 | 22800 | yes | 0 | 지하1층 | -6100 | -6250
2699627 | 지상 1층 | 99.5284 | 14.9293 | 14.9293 | 40004 | yes | -1500 | 지상 1층 | -1500 | -1650
2700539 | 지상 2층 | 502.686 | 75.4029 | 75.4029 | 102800 | yes | 0 | 지상 2층 | 4800 | 4650
2700553 | 지상 2층 | 98.44 | 14.766 | 14.766 | 39800 | yes | 0 | 지상 2층 | 4800 | 4650
2701140 | 지상 3층 | 502.539 | 75.3809 | 75.3808 | 102800 | yes | 0 | 지상 3층 | 9300 | 9150
2701152 | 지상 3층 | 98.44 | 14.766 | 14.766 | 39800 | yes | 0 | 지상 3층 | 9300 | 9150
2701500 | 지상 4층 | 502.539 | 75.3809 | 75.3808 | 102800 | yes | 0 | 지상 4층 | 13400 | 13250
2701512 | 지상 4층 | 98.44 | 14.766 | 14.766 | 39800 | yes | 0 | 지상 4층 | 13400 | 13250
2764954 | 지상 5층 | 502.539 | 75.3809 | 75.3808 | 102800 | yes | 0 | 지상 5층 | 17500 | 17350
2764966 | 지상 5층 | 98.44 | 14.766 | 14.766 | 39800 | yes | 0 | 지상 5층 | 17500 | 17350
2765119 | 지상 6층 | 502.539 | 75.3809 | 75.3808 | 102800 | yes | 0 | 지상 6층 | 21600 | 21450
2765131 | 지상 6층 | 98.44 | 14.766 | 14.766 | 39800 | yes | 0 | 지상 6층 | 21600 | 21450
2765285 | 지상 7층 | 502.686 | 75.4029 | 75.4029 | 102800 | yes | 0 | 지상 7층 | 25700 | 25550
2765297 | 지상 7층 | 98.44 | 14.766 | 14.766 | 39800 | yes | 0 | 지상 7층 | 25700 | 25550
2765450 | 지상 8층 | 502.539 | 75.3809 | 75.3808 | 102800 | yes | 0 | 지상 8층 | 29800 | 29650
2765462 | 지상 8층 | 98.44 | 14.766 | 14.766 | 39800 | yes | 0 | 지상 8층 | 29800 | 29650
2765616 | 지상 9층 | 502.539 | 75.3809 | 75.3808 | 102800 | yes | 0 | 지상 9층 | 33900 | 33750
2765628 | 지상 9층 | 98.44 | 14.766 | 14.766 | 39800 | yes | 0 | 지상 9층 | 33900 | 33750
2765933 | 옥탑층 | 506.45 | 75.9675 | 75.9675 | 102400 | yes | 0 | 옥탑층 | 43400 | 43250
2765945 | 옥탑층 | 96.3 | 14.445 | 14.445 | 39400 | yes | 0 | 옥탑층 | 43400 | 43250
2766004 | 옥탑층 | 54.51 | 8.1765 | 8.1765 | 29600 | yes | 0 | 지붕층 | 47400 | 47250
5871476 | 지하2층 | 7.14 | 1.071 | 1.071 | 11000 | no | 0 | 지하2층 | -10100 | -10250

# IfcSlab: 바닥:SL111-철근콘크리트구조 바닥 150mm_S2 (20)
Type - PredefinedType: FLOOR; Material: KBIMS-콘크리트 150 mm
Type - ID 데이터 - 단가: 0; 유형 마크: S2; 유형 이름: SL111-철근콘크리트구조 바닥 150mm_S2
Type - 그래픽 - 거친 축척 채우기 색상: 0
Type - 기타 - 내화구조여부: yes; 카테고리: 바닥; 주요구조부여부: yes; KBIMS-부위코드: E251; 조달청표준공사코드: AD; 패밀리 이름: 바닥
Type - 시공 - 기능: 내부; 기본 두께: 150 mm
Type - 재료 및 마감재 - 구조 재료: KBIMS-콘크리트
Type - 해석 특성 - 거칠기: 1; 열 저항(R): 0.143403; 열 전달 계수(U): 6.97333 kg/K/s3; 열 질량: 226.665; 흡수율: 9290.3
Type - Pset_SlabCommon - IsExternal: no; ThermalTransmittance: 6.97333 kg/K/s3
Pset_QuantityTakeOff - Reference: SL111-철근콘크리트구조 바닥 150mm_S2; sets with these values: 2
Pset_SlabCommon - LoadBearing: yes; PitchAngle: 0 deg; Reference: SL111-철근콘크리트구조 바닥 150mm_S2
BaseQuantities - Width: 150 mm
공정 - 생성 공정: 새 구성
구속조건 - 매스와 관련됨: no; 룸 경계: yes
구조 - 구조: yes; 보강 철근 피복 - 다른 면: 보강 철근 피복 1 <25 mm>; 보강 철근 피복 - 상단 면: 보강 철근 피복 1 <25 mm>; 보강 철근 피복 - 하단 면: 보강 철근 피복 1 <25 mm>
기타 - 패밀리: 바닥; 유형: SL111-철근콘크리트구조 바닥 150mm_S2; 유형 ID: 7622617; 패밀리 및 유형: 바닥: SL111-철근콘크리트구조 바닥 150mm_S2
치수 - 두께: 150 mm; 코어 두께: 150 mm
Name (바닥:SL111-철근콘크리트구조 바닥 150mm_S2:...) | In | GrossArea (m2) = NetArea (m2) = 면적 (m2) | GrossVolume (m3) = NetVolume (m3) = 체적 (m3) | Perimeter (mm) = 둘레 (mm) | 연관 있음 | 레벨로부터 높이 간격띄우기 (mm) | 레벨 | 상단 기준 레벨 (mm) = 상단 기준 레벨 측량 (mm) = 상단 코어의 입면도 (mm) | 하단 기준 레벨 (mm) = 하단 기준 레벨 측량 (mm) = 하단 코어의 입면도 (mm)
2698939 | 지하1층 | 198.092 | 29.7139 | 63028.8 | yes | 0 | 지하1층 | -6100 | -6250
2698971 | 지하1층 | 249.92 | 37.488 | 73400 | yes | 0 | 지하1층 | -6100 | -6250
2699604 | 지상 1층 | 110.7 | 16.605 | 43400 | yes | 0 | 지상 1층 | 0 | -150
2699611 | 지상 1층 | 97.0101 | 14.5515 | 39600 | yes | 0 | 지상 1층 | 0 | -150
2700124 | 지상 1층 | 51.3695 | 7.70543 | 31004 | yes | -500 | 지상 1층 | -500 | -650
2700546 | 지상 2층 | 337.8 | 50.67 | 81400 | yes | 0 | 지상 2층 | 4800 | 4650
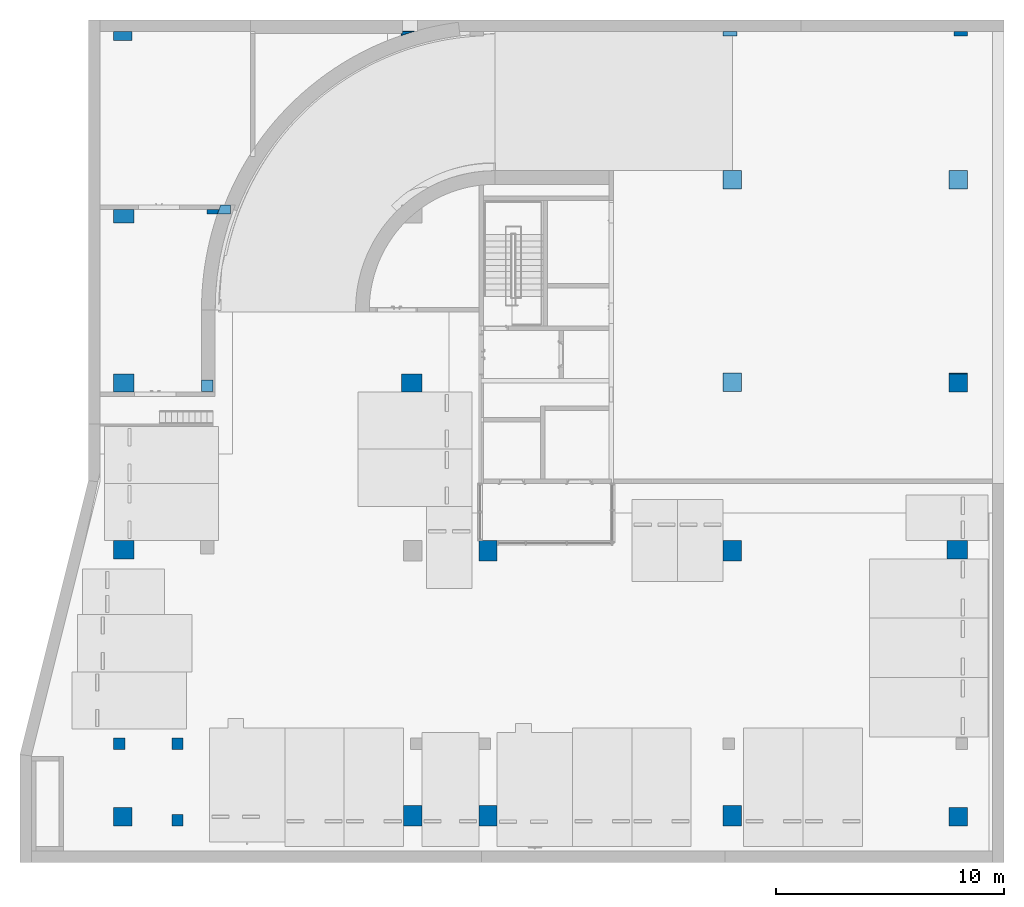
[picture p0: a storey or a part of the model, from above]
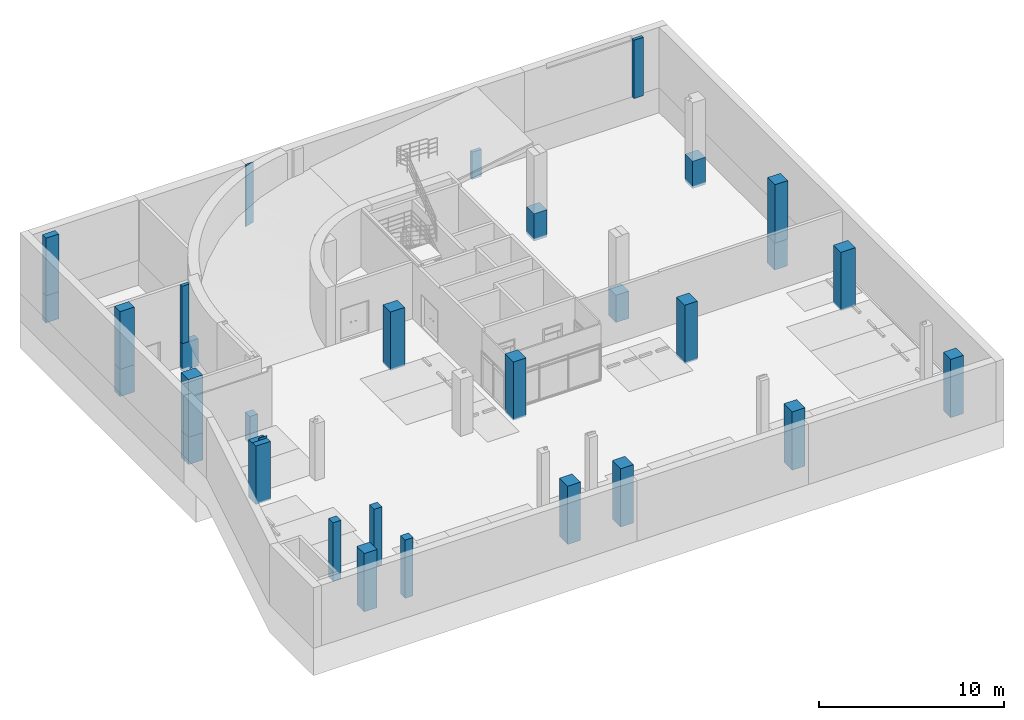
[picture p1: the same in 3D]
Properties of the parts of a building model (IFC2X3), part 33 of 39

# IfcSlab: 바닥:SL111-철근콘크리트구조 바닥 150mm_S2 (20)
Name (바닥:SL111-철근콘크리트구조 바닥 150mm_S2:...) | In | GrossArea (m2) = NetArea (m2) = 면적 (m2) | GrossVolume (m3) = NetVolume (m3) = 체적 (m3) | Perimeter (mm) = 둘레 (mm) | 연관 있음 | 레벨로부터 높이 간격띄우기 (mm) | 레벨 | 상단 기준 레벨 (mm) = 상단 기준 레벨 측량 (mm) = 상단 코어의 입면도 (mm) | 하단 기준 레벨 (mm) = 하단 기준 레벨 측량 (mm) = 하단 코어의 입면도 (mm)
2701145 | 지상 3층 | 337.275 | 50.5913 | 81400 | yes | 0 | 지상 3층 | 9300 | 9150
2701505 | 지상 4층 | 337.8 | 50.67 | 81400 | yes | 0 | 지상 4층 | 13400 | 13250
2764959 | 지상 5층 | 337.8 | 50.67 | 81400 | yes | 0 | 지상 5층 | 17500 | 17350
2765124 | 지상 6층 | 337.275 | 50.5913 | 81400 | yes | 0 | 지상 6층 | 21600 | 21450
2765290 | 지상 7층 | 337.275 | 50.5913 | 81400 | yes | 0 | 지상 7층 | 25700 | 25550
2765455 | 지상 8층 | 337.275 | 50.5913 | 81400 | yes | 0 | 지상 8층 | 29800 | 29650
2765621 | 지상 9층 | 337.275 | 50.5913 | 81400 | yes | 0 | 지상 9층 | 33900 | 33750
2765938 | 옥탑층 | 344.54 | 51.681 | 82200 | yes | 0 | 옥탑층 | 43400 | 43250
2766009 | 옥탑층 | 92.3333 | 13.85 | 47003.7 | no | 0 | 지붕층 | 47400 | 47250
3108693 | 지상 1층 | 93.45 | 14.0175 | 38800 | yes | 0 | 지상 1층 | 0 | -150
3641795 | 지하1층 | 62.37 | 9.3555 | 32400 | yes | 0 | 지하1층 | -6100 | -6250
5319766 | 지상 1층 | 171.19 | 25.6785 | 56400 | yes | 0 | 지상 1층 | 0 | -150
5319826 | 지상 1층 | 117.45 | 17.6175 | 44400 | yes | 0 | 지상 1층 | 0 | -150
5320422 | 지상 1층 | 13.6414 | 2.0462 | 15913.1 | yes | -500 | 지상 1층 | -500 | -650

# IfcSlab: 바닥:SL111-철근콘크리트구조 바닥 150mm_S3 (20)
Type - PredefinedType: FLOOR; Material: KBIMS-콘크리트 150 mm
Type - ID 데이터 - 단가: 0; 유형 마크: S3; 유형 이름: SL111-철근콘크리트구조 바닥 150mm_S3
Type - 그래픽 - 거친 축척 채우기 색상: 0
Type - 기타 - 내화구조여부: yes; 카테고리: 바닥; KBIMS-부위코드: E251; 조달청표준공사코드: AD; 주요구조부여부: yes; 패밀리 이름: 바닥
Type - 시공 - 기능: 내부; 기본 두께: 150 mm
Type - 재료 및 마감재 - 구조 재료: KBIMS-콘크리트
Type - 해석 특성 - 거칠기: 1; 열 저항(R): 0.143403; 열 전달 계수(U): 6.97333 kg/K/s3; 열 질량: 226.665; 흡수율: 9290.3
Type - Pset_SlabCommon - IsExternal: no; ThermalTransmittance: 6.97333 kg/K/s3
Pset_QuantityTakeOff - Reference: SL111-철근콘크리트구조 바닥 150mm_S3; sets with these values: 2
Pset_SlabCommon - LoadBearing: yes; PitchAngle: 0 deg; Reference: SL111-철근콘크리트구조 바닥 150mm_S3
ID 데이터 - 연관 있음: yes
공정 - 생성 공정: 새 구성
구속조건 - 레벨로부터 높이 간격띄우기: 0 mm; 매스와 관련됨: no; 룸 경계: yes
구조 - 구조: yes; 보강 철근 피복 - 다른 면: 보강 철근 피복 1 <25 mm>; 보강 철근 피복 - 상단 면: 보강 철근 피복 1 <25 mm>; 보강 철근 피복 - 하단 면: 보강 철근 피복 1 <25 mm>
기타 - 유형: SL111-철근콘크리트구조 바닥 150mm_S3; 유형 ID: 7622680; 패밀리: 바닥; 패밀리 및 유형: 바닥: SL111-철근콘크리트구조 바닥 150mm_S3
치수 - 두께: 150 mm; 코어 두께: 150 mm
Name (바닥:SL111-철근콘크리트구조 바닥 150mm_S3:...) | In | NetArea (m2) = 면적 (m2) | NetVolume (m3) = 체적 (m3) | 레벨 | 둘레 (mm) | 상단 기준 레벨 (mm) = 상단 기준 레벨 측량 (mm) = 상단 코어의 입면도 (mm) | 하단 기준 레벨 (mm) = 하단 기준 레벨 측량 (mm) = 하단 코어의 입면도 (mm) | GrossArea (m2) | GrossVolume (m3) | Perimeter (mm) | Width (mm)
2698884 | 지하1층 | 238.59 | 35.7886 | 지하1층 | 165699 | -6100 | -6250
2699230 | 지하1층 | 92.9367 | 13.9403 | 지하1층 | 69312.6 | -6100 | -6250 | 92.9355 | 13.9403 | 69312.6 | 150
2699594 | 지상 1층 | 48.6 | 7.29 | 지상 1층 | 34200 | 0 | -150 | 48.6 | 7.29 | 34200 | 150
2699662 | 지상 1층 | 20.485 | 3.07275 | 지상 1층 | 21396.3 | 0 | -150 | 20.485 | 3.07275 | 21396.3 | 150
2699820 | 지상 1층 | 31.25 | 4.6875 | 지상 1층 | 30000 | 0 | -150 | 31.25 | 4.6875 | 30000 | 150
2700560 | 지상 2층 | 122.832 | 18.4249 | 지상 2층 | 93199.8 | 4800 | 4650 | 122.832 | 18.4249 | 93099.8 | 150
2701159 | 지상 3층 | 123.505 | 18.5257 | 지상 3층 | 93199.8 | 9300 | 9150 | 123.505 | 18.5257 | 93199.8 | 150
2701519 | 지상 4층 | 122.993 | 18.4489 | 지상 4층 | 93199.8 | 13400 | 13250 | 122.993 | 18.4489 | 93199.8 | 150
2764973 | 지상 5층 | 122.98 | 18.447 | 지상 5층 | 93199.8 | 17500 | 17350 | 122.98 | 18.447 | 93199.8 | 150
2765138 | 지상 6층 | 123.502 | 18.5254 | 지상 6층 | 93199.8 | 21600 | 21450 | 123.502 | 18.5254 | 93203.5 | 150
2765304 | 지상 7층 | 123.352 | 18.5029 | 지상 7층 | 93199.8 | 25700 | 25550 | 123.352 | 18.5029 | 93207.4 | 150
2765469 | 지상 8층 | 123.502 | 18.5254 | 지상 8층 | 93199.8 | 29800 | 29650 | 123.502 | 18.5254 | 93203.5 | 150
2765635 | 지상 9층 | 123.5 | 18.525 | 지상 9층 | 93199.8 | 33900 | 33750 | 123.5 | 18.525 | 93207.4 | 150
2765952 | 옥탑층 | 109.871 | 16.4807 | 옥탑층 | 96043.9 | 43400 | 43250 | 109.871 | 16.4807 | 96043.9 | 150
2765960 | 옥탑층 | 45.2359 | 6.78538 | 옥탑층 | 28964 | 43400 | 43250 | 45.2359 | 6.78538 | 28964 | 150
3108643 | 지상 1층 | 39.2413 | 5.88619 | 지상 1층 | 29000.7 | 0 | -150 | 39.2413 | 5.88619 | 29000.7 | 150
3108700 | 지상 1층 | 37.7987 | 5.6698 | 지상 1층 | 28199.3 | 0 | -150 | 37.7987 | 5.6698 | 28199.3 | 150
3151812 | 지상 1층 | 40.9 | 6.13501 | 지상 1층 | 38400 | 0 | -150 | 40.9 | 6.13501 | 38400 | 150
5319956 | 지상 1층 | 26.5407 | 3.98111 | 지상 1층 | 26800 | 0 | -150 | 26.5407 | 3.98111 | 26800 | 150
5320227 | 지상 1층 | 27.26 | 4.089 | 지상 1층 | 24600 | 0 | -150 | 27.26 | 4.089 | 24600 | 150

# IfcSlab: 바닥:SL111-철근콘크리트구조 바닥 150mm_S4 (16)
Type - PredefinedType: FLOOR; Material: KBIMS-콘크리트 150 mm
Type - ID 데이터 - 단가: 0; 유형 마크: S4; 유형 이름: SL111-철근콘크리트구조 바닥 150mm_S4
Type - 그래픽 - 거친 축척 채우기 색상: 0
Type - 기타 - 내화구조여부: yes; 카테고리: 바닥; 주요구조부여부: yes; KBIMS-부위코드: E251; 조달청표준공사코드: AD; 패밀리 이름: 바닥
Type - 시공 - 기능: 내부; 기본 두께: 150 mm
Type - 재료 및 마감재 - 구조 재료: KBIMS-콘크리트
Type - 해석 특성 - 거칠기: 1; 열 저항(R): 0.143403; 열 전달 계수(U): 6.97333 kg/K/s3; 열 질량: 226.665; 흡수율: 9290.3
Type - Pset_SlabCommon - IsExternal: no; ThermalTransmittance: 6.97333 kg/K/s3
Pset_QuantityTakeOff - Reference: SL111-철근콘크리트구조 바닥 150mm_S4; sets with these values: 2
Pset_SlabCommon - LoadBearing: yes; PitchAngle: 0 deg; Reference: SL111-철근콘크리트구조 바닥 150mm_S4
ID 데이터 - 연관 있음: yes
공정 - 생성 공정: 새 구성
구속조건 - 매스와 관련됨: no; 룸 경계: yes
구조 - 구조: yes; 보강 철근 피복 - 다른 면: 보강 철근 피복 1 <25 mm>; 보강 철근 피복 - 상단 면: 보강 철근 피복 1 <25 mm>; 보강 철근 피복 - 하단 면: 보강 철근 피복 1 <25 mm>
기타 - 패밀리: 바닥; 유형: SL111-철근콘크리트구조 바닥 150mm_S4; 유형 ID: 7622712; 패밀리 및 유형: 바닥: SL111-철근콘크리트구조 바닥 150mm_S4
치수 - 두께: 150 mm; 코어 두께: 150 mm
Name (바닥:SL111-철근콘크리트구조 바닥 150mm_S4:...) | In | GrossArea (m2) | NetArea (m2) = 면적 (m2) | NetVolume (m3) = 체적 (m3) | Perimeter (mm) | 레벨로부터 높이 간격띄우기 (mm) | 레벨 | 둘레 (mm) | 상단 기준 레벨 (mm) = 상단 기준 레벨 측량 (mm) = 상단 코어의 입면도 (mm) | 하단 기준 레벨 (mm) = 하단 기준 레벨 측량 (mm) = 하단 코어의 입면도 (mm)
3171192 | 지상 2층 | 10.2599 | 10.2599 | 1.53899 | 15000 | 0 | 지상 2층 | 15000 | 4800 | 4650 | BaseQuantities - GrossVolume: 1.53899 m3; Width: 150 mm
3171206:2 | 지상 2층 | 11.4401 | 28.8393 | 4.3259 | 14000 | -50 | 지상 2층 | 35860 | 4750 | 4600
3171958 | 지상 3층 | 10.2599 | 10.2599 | 1.53899 | 15000 | 0 | 지상 3층 | 15000 | 9300 | 9150 | BaseQuantities - GrossVolume: 1.53899 m3; Width: 150 mm
3171972:2 | 지상 3층 | 11.44 | 29.59 | 4.43851 | 14000 | -50 | 지상 3층 | 31600 | 9250 | 9100
3172011 | 지상 4층 | 10.2599 | 10.2599 | 1.53899 | 15000 | 0 | 지상 4층 | 15000 | 13400 | 13250 | BaseQuantities - GrossVolume: 1.53899 m3; Width: 150 mm
3172025:2 | 지상 4층 | 11.44 | 29.59 | 4.43851 | 14000 | -50 | 지상 4층 | 31600 | 13350 | 13200
3172064 | 지상 5층 | 10.2599 | 10.2599 | 1.53899 | 15000 | 0 | 지상 5층 | 15000 | 17500 | 17350 | BaseQuantities - GrossVolume: 1.53899 m3; Width: 150 mm
3172078 | 지상 5층 |  | 29.04 | 4.356 |  | -50 | 지상 5층 | 31600 | 17450 | 17300
3172117 | 지상 6층 | 10.2599 | 10.2599 | 1.53899 | 15000 | 0 | 지상 6층 | 15000 | 21600 | 21450 | BaseQuantities - GrossVolume: 1.53899 m3; Width: 150 mm
3172131 | 지상 6층 |  | 29.59 | 4.43851 |  | -50 | 지상 6층 | 31600 | 21550 | 21400
3172170 | 지상 7층 | 10.2599 | 10.2599 | 1.53899 | 15000 | 0 | 지상 7층 | 15000 | 25700 | 25550 | BaseQuantities - GrossVolume: 1.53899 m3; Width: 150 mm
3172184 | 지상 7층 |  | 29.59 | 4.43851 |  | -50 | 지상 7층 | 31600 | 25650 | 25500
3172223 | 지상 8층 | 10.2599 | 10.2599 | 1.53899 | 15000 | 0 | 지상 8층 | 15000 | 29800 | 29650 | BaseQuantities - GrossVolume: 1.53899 m3; Width: 150 mm
3172237 | 지상 8층 |  | 29.59 | 4.43851 |  | -50 | 지상 8층 | 31600 | 29750 | 29600
3172276 | 지상 9층 | 10.2599 | 10.2599 | 1.53899 | 15000 | 0 | 지상 9층 | 15000 | 33900 | 33750 | BaseQuantities - GrossVolume: 1.53899 m3; Width: 150 mm
3172290 | 지상 9층 |  | 29.59 | 4.43851 |  | -50 | 지상 9층 | 31600 | 33850 | 33700

# IfcSlab: 바닥:SL111-철근콘크리트구조 바닥 150mm_S4 (3)
Type - PredefinedType: FLOOR
Type - ID 데이터 - 단가: 0; 유형 마크: S4; 유형 이름: SL111-철근콘크리트구조 바닥 150mm_S4
Type - 그래픽 - 거친 축척 채우기 색상: 0
Type - 기타 - 내화구조여부: yes; 카테고리: 바닥; 주요구조부여부: yes; KBIMS-부위코드: E251; 조달청표준공사코드: AD; 패밀리 이름: 바닥
Type - 시공 - 기능: 내부; 기본 두께: 150 mm
Type - 재료 및 마감재 - 구조 재료: KBIMS-콘크리트
Type - 해석 특성 - 거칠기: 1; 열 저항(R): 0.143403; 열 전달 계수(U): 6.97333 kg/K/s3; 열 질량: 226.665; 흡수율: 9290.3
Type - Pset_SlabCommon - IsExternal: no; ThermalTransmittance: 6.97333 kg/K/s3
Material: KBIMS-콘크리트 150 mm
Pset_QuantityTakeOff - Reference: SL111-철근콘크리트구조 바닥 150mm_S4; sets with these values: 2
Pset_SlabCommon - LoadBearing: yes; PitchAngle: 0 deg; Reference: SL111-철근콘크리트구조 바닥 150mm_S4
ID 데이터 - 연관 있음: yes
공정 - 생성 공정: 새 구성
구속조건 - 매스와 관련됨: no; 룸 경계: yes; 레벨로부터 높이 간격띄우기: -50 mm
구조 - 구조: yes; 보강 철근 피복 - 다른 면: 보강 철근 피복 1 <25 mm>; 보강 철근 피복 - 상단 면: 보강 철근 피복 1 <25 mm>; 보강 철근 피복 - 하단 면: 보강 철근 피복 1 <25 mm>
기타 - 패밀리: 바닥; 유형: SL111-철근콘크리트구조 바닥 150mm_S4; 유형 ID: 7622712; 패밀리 및 유형: 바닥: SL111-철근콘크리트구조 바닥 150mm_S4
치수 - 두께: 150 mm; 코어 두께: 150 mm
Name (바닥:SL111-철근콘크리트구조 바닥 150mm_S4:...) | In | GrossArea (m2) | NetArea (m2) = 면적 (m2) | NetVolume (m3) = 체적 (m3) | Perimeter (mm) | 레벨 | 둘레 (mm) | 상단 기준 레벨 (mm) = 상단 기준 레벨 측량 (mm) = 상단 코어의 입면도 (mm) | 하단 기준 레벨 (mm) = 하단 기준 레벨 측량 (mm) = 하단 코어의 입면도 (mm)
3171206 | 지상 2층 | 17.3993 | 28.8393 | 4.3259 | 21860 | 지상 2층 | 35860 | 4750 | 4600
3171972 | 지상 3층 | 18.15 | 29.59 | 4.43851 | 17600 | 지상 3층 | 31600 | 9250 | 9100
3172025 | 지상 4층 | 18.15 | 29.59 | 4.43851 | 17600 | 지상 4층 | 31600 | 13350 | 13200

# IfcSlab: 바닥:SL111-철근콘크리트구조 바닥 150mm_S5, 바닥:SL111-철근콘크리트구조 바닥 150mm_S5:2699257
In: 지하1층
Type - PredefinedType: FLOOR; Material: KBIMS-콘크리트 150 mm
Type - ID 데이터 - 단가: 0; 유형 마크: S5; 유형 이름: SL111-철근콘크리트구조 바닥 150mm_S5
Type - 그래픽 - 거친 축척 채우기 색상: 0
Type - 기타 - 내화구조여부: yes; 카테고리: 바닥; 주요구조부여부: yes; KBIMS-부위코드: E251; 조달청표준공사코드: AD; 패밀리 이름: 바닥
Type - 시공 - 기능: 내부; 기본 두께: 150 mm
Type - 재료 및 마감재 - 구조 재료: KBIMS-콘크리트
Type - 해석 특성 - 거칠기: 1; 열 저항(R): 0.143403; 열 전달 계수(U): 6.97333 kg/K/s3; 열 질량: 226.665; 흡수율: 9290.3
Type - Pset_SlabCommon - IsExternal: no; ThermalTransmittance: 6.97333 kg/K/s3
Pset_QuantityTakeOff - Reference: SL111-철근콘크리트구조 바닥 150mm_S5; sets with these values: 2
Pset_SlabCommon - LoadBearing: yes; PitchAngle: 0 deg; Reference: SL111-철근콘크리트구조 바닥 150mm_S5
BaseQuantities - GrossArea: 29.25 m2; NetArea: 29.25 m2; GrossVolume: 4.3875 m3; NetVolume: 4.3875 m3; Perimeter: 24500 mm; Width: 150 mm
ID 데이터 - 연관 있음: yes
공정 - 생성 공정: 새 구성
구속조건 - 레벨로부터 높이 간격띄우기: 0 mm; 매스와 관련됨: no; 레벨: 지하1층; 룸 경계: yes
구조 - 구조: yes; 보강 철근 피복 - 다른 면: 보강 철근 피복 1 <25 mm>; 보강 철근 피복 - 상단 면: 보강 철근 피복 1 <25 mm>; 보강 철근 피복 - 하단 면: 보강 철근 피복 1 <25 mm>
기타 - 패밀리: 바닥; 유형: SL111-철근콘크리트구조 바닥 150mm_S5; 유형 ID: 7625545; 패밀리 및 유형: 바닥: SL111-철근콘크리트구조 바닥 150mm_S5
치수 - 두께: 150 mm; 둘레: 24500 mm; 면적: 29.25 m2; 상단 기준 레벨: -6100 mm; 상단 기준 레벨 측량: -6100 mm; 상단 코어의 입면도: -6100 mm; 체적: 4.3875 m3; 코어 두께: 150 mm; 하단 기준 레벨: -6250 mm; 하단 기준 레벨 측량: -6250 mm; 하단 코어의 입면도: -6250 mm

# IfcSlab: 바닥:SL111-철근콘크리트구조 바닥 200mm_S11 (5)
In: 지상 1층
Type - PredefinedType: FLOOR; Material: KBIMS-콘크리트 200 mm
Type - ID 데이터 - 단가: 0; 유형 마크: S11; 유형 이름: SL111-철근콘크리트구조 바닥 200mm_S11
Type - 그래픽 - 거친 축척 채우기 색상: 0
Type - 기타 - 내화구조여부: yes; 카테고리: 바닥; 주요구조부여부: yes; KBIMS-부위코드: E251; 조달청표준공사코드: AD; 패밀리 이름: 바닥
Type - 시공 - 기능: 내부; 기본 두께: 200 mm
Type - 재료 및 마감재 - 구조 재료: KBIMS-콘크리트
Type - 해석 특성 - 거칠기: 1; 열 저항(R): 0.191205; 열 전달 계수(U): 5.23 kg/K/s3; 열 질량: 302.22; 흡수율: 9290.3
Type - Pset_SlabCommon - IsExternal: no; ThermalTransmittance: 5.23 kg/K/s3
Pset_QuantityTakeOff - Reference: SL111-철근콘크리트구조 바닥 200mm_S11; sets with these values: 2
Pset_SlabCommon - LoadBearing: yes; PitchAngle: 0 deg; Reference: SL111-철근콘크리트구조 바닥 200mm_S11
BaseQuantities - Width: 200 mm
공정 - 생성 공정: 새 구성
구속조건 - 매스와 관련됨: no; 레벨: 지상 1층
구조 - 구조: yes; 보강 철근 피복 - 다른 면: 보강 철근 피복 1 <25 mm>; 보강 철근 피복 - 상단 면: 보강 철근 피복 1 <25 mm>; 보강 철근 피복 - 하단 면: 보강 철근 피복 1 <25 mm>
기타 - 패밀리: 바닥; 유형: SL111-철근콘크리트구조 바닥 200mm_S11; 유형 ID: 7622781; 패밀리 및 유형: 바닥: SL111-철근콘크리트구조 바닥 200mm_S11
치수 - 두께: 200 mm; 코어 두께: 200 mm
Name (바닥:SL111-철근콘크리트구조 바닥 200mm_S11:...) | GrossArea (m2) = NetArea (m2) = 면적 (m2) | GrossVolume (m3) = NetVolume (m3) = 체적 (m3) | Perimeter (mm) = 둘레 (mm) | 연관 있음 | 레벨로부터 높이 간격띄우기 (mm) = 상단 기준 레벨 (mm) = 상단 기준 레벨 측량 (mm) = 상단 코어의 입면도 (mm) | 룸 경계 | 하단 기준 레벨 (mm) = 하단 기준 레벨 측량 (mm) = 하단 코어의 입면도 (mm)
3108579 | 76.996 | 15.3992 | 104120 | yes | 0 | yes | -200 | ID 데이터 - 마크: SITE
3108996 | 10.5601 | 2.11201 | 16400 | yes | -2100 | no | -2300 | ID 데이터 - 마크: SITE
5364923 | 12.9441 | 2.58881 | 19380 | yes | -1500 | yes | -1700
5364943 | 10.1601 | 2.03201 | 15900 | yes | -500 | yes | -700
7622827 | 24.9553 | 4.99106 | 49958.1 | no | 0 | yes | -200

# IfcSlab: 바닥:SL111-철근콘크리트구조 바닥 200mm_S12 (2)
In: 지상 1층
Type - PredefinedType: FLOOR; Material: KBIMS-콘크리트 200 mm
Type - ID 데이터 - 단가: 0; 유형 마크: S12; 유형 이름: SL111-철근콘크리트구조 바닥 200mm_S12
Type - 그래픽 - 거친 축척 채우기 색상: 0
Type - 기타 - 내화구조여부: yes; 카테고리: 바닥; 주요구조부여부: yes; KBIMS-부위코드: E251; 조달청표준공사코드: AD; 패밀리 이름: 바닥
Type - 시공 - 기능: 내부; 기본 두께: 200 mm
Type - 재료 및 마감재 - 구조 재료: KBIMS-콘크리트
Type - 해석 특성 - 거칠기: 1; 열 저항(R): 0.191205; 열 전달 계수(U): 5.23 kg/K/s3; 열 질량: 302.22; 흡수율: 9290.3
Type - Pset_SlabCommon - IsExternal: no; ThermalTransmittance: 5.23 kg/K/s3
Pset_QuantityTakeOff - Reference: SL111-철근콘크리트구조 바닥 200mm_S12; sets with these values: 2
Pset_SlabCommon - LoadBearing: yes; PitchAngle: 0 deg; Reference: SL111-철근콘크리트구조 바닥 200mm_S12
BaseQuantities - Width: 200 mm
ID 데이터 - 연관 있음: yes
공정 - 생성 공정: 새 구성
구속조건 - 매스와 관련됨: no; 레벨: 지상 1층
구조 - 구조: yes; 보강 철근 피복 - 다른 면: 보강 철근 피복 1 <25 mm>; 보강 철근 피복 - 상단 면: 보강 철근 피복 1 <25 mm>; 보강 철근 피복 - 하단 면: 보강 철근 피복 1 <25 mm>
기타 - 패밀리: 바닥; 유형: SL111-철근콘크리트구조 바닥 200mm_S12; 유형 ID: 7623032; 패밀리 및 유형: 바닥: SL111-철근콘크리트구조 바닥 200mm_S12
치수 - 두께: 200 mm; 코어 두께: 200 mm
Name (바닥:SL111-철근콘크리트구조 바닥 200mm_S12:...) | GrossArea (m2) = NetArea (m2) = 면적 (m2) | GrossVolume (m3) = NetVolume (m3) = 체적 (m3) | Perimeter (mm) | 레벨로부터 높이 간격띄우기 (mm) = 상단 기준 레벨 (mm) = 상단 기준 레벨 측량 (mm) = 상단 코어의 입면도 (mm) | 룸 경계 | 둘레 (mm) | 하단 기준 레벨 (mm) = 하단 기준 레벨 측량 (mm) = 하단 코어의 입면도 (mm)
2700453 | 35.3825 | 7.0765 | 23800.8 | -2100 | no | 24600.8 | -2300
3107901 | 43.5813 | 8.71627 | 32517.4 | 0 | yes | 32517.4 | -200 | ID 데이터 - 마크: SITE

# IfcSlab: 바닥:SL111-철근콘크리트구조 바닥 200mm_S13 (4)
In: 지상 1층
Type - PredefinedType: FLOOR; Material: KBIMS-콘크리트 200 mm
Type - ID 데이터 - 단가: 0; 유형 마크: S13; 유형 이름: SL111-철근콘크리트구조 바닥 200mm_S13
Type - 그래픽 - 거친 축척 채우기 색상: 0
Type - 기타 - 내화구조여부: yes; 카테고리: 바닥; 주요구조부여부: yes; KBIMS-부위코드: E251; 조달청표준공사코드: AD; 패밀리 이름: 바닥
Type - 시공 - 기능: 내부; 기본 두께: 200 mm
Type - 재료 및 마감재 - 구조 재료: KBIMS-콘크리트
Type - 해석 특성 - 거칠기: 1; 열 저항(R): 0.191205; 열 전달 계수(U): 5.23 kg/K/s3; 열 질량: 302.22; 흡수율: 9290.3
Type - Pset_SlabCommon - IsExternal: no; ThermalTransmittance: 5.23 kg/K/s3
Pset_QuantityTakeOff - Reference: SL111-철근콘크리트구조 바닥 200mm_S13; sets with these values: 2
Pset_SlabCommon - LoadBearing: yes; PitchAngle: 0 deg; Reference: SL111-철근콘크리트구조 바닥 200mm_S13
BaseQuantities - Width: 200 mm
ID 데이터 - 연관 있음: yes
공정 - 생성 공정: 새 구성
구속조건 - 매스와 관련됨: no; 레벨: 지상 1층
구조 - 구조: yes; 보강 철근 피복 - 다른 면: 보강 철근 피복 1 <25 mm>; 보강 철근 피복 - 상단 면: 보강 철근 피복 1 <25 mm>; 보강 철근 피복 - 하단 면: 보강 철근 피복 1 <25 mm>
기타 - 패밀리: 바닥; 유형: SL111-철근콘크리트구조 바닥 200mm_S13; 유형 ID: 7623064; 패밀리 및 유형: 바닥: SL111-철근콘크리트구조 바닥 200mm_S13
치수 - 두께: 200 mm; 코어 두께: 200 mm
Name (바닥:SL111-철근콘크리트구조 바닥 200mm_S13:...) | GrossArea (m2) = NetArea (m2) = 면적 (m2) | GrossVolume (m3) = NetVolume (m3) = 체적 (m3) | Perimeter (mm) = 둘레 (mm) | 마크 | 룸 경계 | 레벨로부터 높이 간격띄우기 (mm) = 상단 기준 레벨 (mm) = 상단 기준 레벨 측량 (mm) = 상단 코어의 입면도 (mm) | 하단 기준 레벨 (mm) = 하단 기준 레벨 측량 (mm) = 하단 코어의 입면도 (mm)
2700477 | 53.637 | 10.7274 | 29503.7 | SITE | yes | -550 | -750
3186441 | 22.1 | 4.42 | 19800 | SITE | no | 500 | 300
3186777 | 15.9249 | 3.18499 | 17900 | SITE | no | 200 | 0
5399430 | 6.4 | 1.28 | 17600 |  | no | -550 | -750

# IfcSlab: 바닥:SL111-철근콘크리트구조 바닥 200mm_S3, 바닥:SL111-철근콘크리트구조 바닥 200mm_S3:2699048
In: 지하1층
Type - PredefinedType: FLOOR; Material: KBIMS-콘크리트 200 mm
Type - ID 데이터 - 단가: 0; 유형 마크: S3; 유형 이름: SL111-철근콘크리트구조 바닥 200mm_S3
Type - 그래픽 - 거친 축척 채우기 색상: 0
Type - 기타 - 내화구조여부: yes; 카테고리: 바닥; 주요구조부여부: yes; KBIMS-부위코드: E251; 조달청표준공사코드: AD; 패밀리 이름: 바닥
Type - 시공 - 기능: 내부; 기본 두께: 200 mm
Type - 재료 및 마감재 - 구조 재료: KBIMS-콘크리트
Type - 해석 특성 - 거칠기: 1; 열 저항(R): 0.191205; 열 전달 계수(U): 5.23 kg/K/s3; 열 질량: 302.22; 흡수율: 9290.3
Type - Pset_SlabCommon - IsExternal: no; ThermalTransmittance: 5.23 kg/K/s3
Pset_QuantityTakeOff - Reference: SL111-철근콘크리트구조 바닥 200mm_S3; sets with these values: 2
Pset_SlabCommon - LoadBearing: yes; PitchAngle: 0 deg; Reference: SL111-철근콘크리트구조 바닥 200mm_S3
BaseQuantities - GrossArea: 8.59373 m2; NetArea: 8.59373 m2; GrossVolume: 1.71875 m3; NetVolume: 1.71875 m3; Perimeter: 17476.4 mm; Width: 200 mm
ID 데이터 - 연관 있음: yes
공정 - 생성 공정: 새 구성
구속조건 - 레벨로부터 높이 간격띄우기: 0 mm; 매스와 관련됨: no; 레벨: 지하1층; 룸 경계: yes
구조 - 구조: yes; 보강 철근 피복 - 다른 면: 보강 철근 피복 1 <25 mm>; 보강 철근 피복 - 상단 면: 보강 철근 피복 1 <25 mm>; 보강 철근 피복 - 하단 면: 보강 철근 피복 1 <25 mm>
기타 - 패밀리: 바닥; 유형: SL111-철근콘크리트구조 바닥 200mm_S3; 유형 ID: 7625594; 패밀리 및 유형: 바닥: SL111-철근콘크리트구조 바닥 200mm_S3
치수 - 두께: 200 mm; 둘레: 17476.4 mm; 면적: 8.59373 m2; 상단 기준 레벨: -6100 mm; 상단 기준 레벨 측량: -6100 mm; 상단 코어의 입면도: -6100 mm; 체적: 1.71875 m3; 코어 두께: 200 mm; 하단 기준 레벨: -6300 mm; 하단 기준 레벨 측량: -6300 mm; 하단 코어의 입면도: -6300 mm

# IfcSlab: 바닥:SL111-철근콘크리트구조 바닥 200mm_S4 (5)
Type - PredefinedType: FLOOR; Material: KBIMS-콘크리트 200 mm
Type - ID 데이터 - 단가: 0; 유형 마크: S4; 유형 이름: SL111-철근콘크리트구조 바닥 200mm_S4
Type - 그래픽 - 거친 축척 채우기 색상: 0
Type - 기타 - 내화구조여부: yes; 카테고리: 바닥; 주요구조부여부: yes; KBIMS-부위코드: E251; 조달청표준공사코드: AD; 패밀리 이름: 바닥
Type - 시공 - 기능: 내부; 기본 두께: 200 mm
Type - 재료 및 마감재 - 구조 재료: KBIMS-콘크리트
Type - 해석 특성 - 거칠기: 1; 열 저항(R): 0.191205; 열 전달 계수(U): 5.23 kg/K/s3; 열 질량: 302.22; 흡수율: 9290.3
Type - Pset_SlabCommon - IsExternal: no; ThermalTransmittance: 5.23 kg/K/s3
Pset_QuantityTakeOff - Reference: SL111-철근콘크리트구조 바닥 200mm_S4; sets with these values: 2
Pset_SlabCommon - LoadBearing: yes; Reference: SL111-철근콘크리트구조 바닥 200mm_S4
ID 데이터 - 연관 있음: yes
공정 - 생성 공정: 새 구성
구속조건 - 매스와 관련됨: no; 룸 경계: yes
구조 - 구조: yes; 보강 철근 피복 - 다른 면: 보강 철근 피복 1 <25 mm>; 보강 철근 피복 - 상단 면: 보강 철근 피복 1 <25 mm>; 보강 철근 피복 - 하단 면: 보강 철근 피복 1 <25 mm>
기타 - 패밀리: 바닥; 유형: SL111-철근콘크리트구조 바닥 200mm_S4; 유형 ID: 7623096; 패밀리 및 유형: 바닥: SL111-철근콘크리트구조 바닥 200mm_S4
치수 - 두께: 200 mm
Name (바닥:SL111-철근콘크리트구조 바닥 200mm_S4:...) | In | PitchAngle (deg) | GrossArea (m2) | NetArea (m2) = 면적 (m2) | GrossVolume (m3) | NetVolume (m3) = 체적 (m3) | Perimeter (mm) | Width (mm) | 레벨로부터 높이 간격띄우기 (mm) | 레벨 | 둘레 (mm) | 상단 기준 레벨 (mm) = 상단 기준 레벨 측량 (mm) = 상단 코어의 입면도 (mm) | 코어 두께 (mm) | 하단 기준 레벨 (mm) = 하단 기준 레벨 측량 (mm) = 하단 코어의 입면도 (mm)
2699313 | 지하1층 | 0 | 87.2234 | 87.2234 | 17.4447 | 17.4447 | 43600 | 200 | 0 | 지하1층 | 43600 | -6100 | 200 | -6300
2699679 | 지상 1층 | 6.2773 | 10.0603 | 10.0603 | 2.02419 | 2.01205 | 14060.3 | 201.206 | -550 | 지상 1층 | 14000
3170833 | 지상 1층 | 0 |  | 30.76 |  | 6.15199 |  |  | -600 | 지상 1층 | 32400 | -600 | 200 | -800
5329636 | 지상 1층 | 0 | 22.5368 | 22.5368 | 4.50736 | 4.50736 | 27702.9 | 200 | -550 | 지상 1층 | 27702.9 | -550 | 200 | -750
5362917 | 지상 1층 | 0 | 17.7 | 17.7 | 3.54 | 3.54 | 17800 | 200 | 0 | 지상 1층 | 17800 | 0 | 200 | -200

# IfcSlab: 바닥:SL111-철근콘크리트구조 바닥 200mm_S6, 바닥:SL111-철근콘크리트구조 바닥 200mm_S6:2699070
In: 지하1층
Type - PredefinedType: FLOOR; Material: KBIMS-콘크리트 200 mm
Type - ID 데이터 - 단가: 0; 유형 이름: SL111-철근콘크리트구조 바닥 200mm_S6
Type - 그래픽 - 거친 축척 채우기 색상: 0
Type - 기타 - 내화구조여부: yes; 카테고리: 바닥; 주요구조부여부: yes; KBIMS-부위코드: E251; 조달청표준공사코드: AD; 패밀리 이름: 바닥
Type - 시공 - 기능: 내부; 기본 두께: 200 mm
Type - 재료 및 마감재 - 구조 재료: KBIMS-콘크리트
Type - 해석 특성 - 거칠기: 1; 열 저항(R): 0.191205; 열 전달 계수(U): 5.23 kg/K/s3; 열 질량: 302.22; 흡수율: 9290.3
Type - Pset_SlabCommon - IsExternal: no; ThermalTransmittance: 5.23 kg/K/s3
Pset_QuantityTakeOff - Reference: SL111-철근콘크리트구조 바닥 200mm_S6; sets with these values: 2
Pset_SlabCommon - LoadBearing: yes; PitchAngle: 0 deg; Reference: SL111-철근콘크리트구조 바닥 200mm_S6
BaseQuantities - GrossArea: 114.006 m2; NetArea: 114.006 m2; GrossVolume: 22.8012 m3; NetVolume: 22.8012 m3; Perimeter: 57055.9 mm; Width: 200 mm
ID 데이터 - 연관 있음: yes
공정 - 생성 공정: 새 구성
구속조건 - 레벨로부터 높이 간격띄우기: 0 mm; 매스와 관련됨: no; 레벨: 지하1층; 룸 경계: yes
구조 - 구조: yes; 보강 철근 피복 - 다른 면: 보강 철근 피복 1 <25 mm>; 보강 철근 피복 - 상단 면: 보강 철근 피복 1 <25 mm>; 보강 철근 피복 - 하단 면: 보강 철근 피복 1 <25 mm>
기타 - 패밀리: 바닥; 유형: SL111-철근콘크리트구조 바닥 200mm_S6; 유형 ID: 7625577; 패밀리 및 유형: 바닥: SL111-철근콘크리트구조 바닥 200mm_S6
치수 - 두께: 200 mm; 둘레: 57055.9 mm; 면적: 114.006 m2; 상단 기준 레벨: -6100 mm; 상단 기준 레벨 측량: -6100 mm; 상단 코어의 입면도: -6100 mm; 체적: 22.8012 m3; 코어 두께: 200 mm; 하단 기준 레벨: -6300 mm; 하단 기준 레벨 측량: -6300 mm; 하단 코어의 입면도: -6300 mm

# IfcSlab: 바닥:SL111-철근콘크리트구조 바닥 300mm_RaS1, 바닥:SL111-철근콘크리트구조 바닥 300mm_RaS1:2698995
In: 지하1층
Type - PredefinedType: FLOOR; Material: KBIMS-콘크리트 300 mm
Type - ID 데이터 - 단가: 0; 유형 마크: RaS1; 유형 이름: SL111-철근콘크리트구조 바닥 300mm_RaS1
Type - 그래픽 - 거친 축척 채우기 색상: 0
Type - 기타 - 내화구조여부: yes; 카테고리: 바닥; 주요구조부여부: yes; KBIMS-부위코드: E251; 조달청표준공사코드: AD; 패밀리 이름: 바닥
Type - 시공 - 기능: 내부; 기본 두께: 300 mm
Type - 재료 및 마감재 - 구조 재료: KBIMS-콘크리트
Type - 해석 특성 - 거칠기: 1; 열 저항(R): 0.286807; 열 전달 계수(U): 3.48667 kg/K/s3; 열 질량: 453.33; 흡수율: 9290.3
Type - Pset_SlabCommon - IsExternal: no; ThermalTransmittance: 3.48667 kg/K/s3
Pset_QuantityTakeOff - Reference: SL111-철근콘크리트구조 바닥 300mm_RaS1; sets with these values: 2
Pset_SlabCommon - LoadBearing: yes; PitchAngle: 0 deg; Reference: SL111-철근콘크리트구조 바닥 300mm_RaS1
BaseQuantities - NetArea: 35.1015 m2; NetVolume: 5.345 m3
ID 데이터 - 연관 있음: yes
공정 - 생성 공정: 새 구성
구속조건 - 레벨로부터 높이 간격띄우기: 0 mm; 매스와 관련됨: no; 레벨: 지하1층; 룸 경계: yes
구조 - 구조: yes; 보강 철근 피복 - 다른 면: 보강 철근 피복 1 <25 mm>; 보강 철근 피복 - 상단 면: 보강 철근 피복 1 <25 mm>; 보강 철근 피복 - 하단 면: 보강 철근 피복 1 <25 mm>
기타 - 패밀리: 바닥; 유형: SL111-철근콘크리트구조 바닥 300mm_RaS1; 유형 ID: 7641959; 패밀리 및 유형: 바닥: SL111-철근콘크리트구조 바닥 300mm_RaS1
치수 - 두께: 300 mm; 둘레: 23836.8 mm; 면적: 35.1015 m2; 상단 기준 레벨: -6100 mm; 상단 기준 레벨 측량: -6100 mm; 상단 코어의 입면도: -6100 mm; 체적: 5.345 m3; 코어 두께: 300 mm; 하단 기준 레벨: -6400 mm; 하단 기준 레벨 측량: -6400 mm; 하단 코어의 입면도: -6400 mm

# IfcSlab: 바닥:SL441-목재블록 바닥 THK38 (3)
In: 지상 1층
Type - PredefinedType: FLOOR; Material: KBIMS-목재블록 30 mm
Type - ID 데이터 - 단가: 0; 유형 이름: SL441-목재블록 바닥 THK38
Type - 그래픽 - 거친 축척 채우기 색상: 0
Type - 기타 - 카테고리: 바닥; KBIMS-부위코드: E25; 불연성재료: 준불연재료; 조달청표준공사코드: AOA111; 패밀리 이름: 바닥
Type - 시공 - 기능: 내부; 기본 두께: 30 mm
Type - 재료 및 마감재 - 구조 재료: KBIMS-목재블록
Type - 해석 특성 - 거칠기: 1; 흡수율: 9290.3
Type - Pset_SlabCommon - IsExternal: no
Pset_QuantityTakeOff - Reference: SL441-목재블록 바닥 THK38; sets with these values: 2
Pset_SlabCommon - PitchAngle: 0 deg; LoadBearing: no; Reference: SL441-목재블록 바닥 THK38
BaseQuantities - Width: 30 mm
ID 데이터 - 연관 있음: no
공정 - 생성 공정: 새 구성
구속조건 - 매스와 관련됨: no; 레벨: 지상 1층; 룸 경계: no
구조 - 구조: no
기타 - 패밀리: 바닥; 유형: SL441-목재블록 바닥 THK38; 유형 ID: 7432096; 패밀리 및 유형: 바닥: SL441-목재블록 바닥 THK38
치수 - 두께: 30 mm
Name (바닥:SL441-목재블록 바닥 THK38:...) | GrossArea (m2) = NetArea (m2) = 면적 (m2) | GrossVolume (m3) = NetVolume (m3) = 체적 (m3) | Perimeter (mm) = 둘레 (mm) | 레벨로부터 높이 간격띄우기 (mm) = 상단 기준 레벨 (mm) | 하단 기준 레벨 (mm)
5399599 | 60.6087 | 1.81826 | 33980 | -520 | -550
5399621 | 18.038 | 0.54114 | 18240 | 530 | 500
5399630 | 15.2389 | 0.457168 | 17340 | 230 | 200

# IfcSlab: 일체형 계단참:일체형 계단참 150mm_철근콘크리트 (49)
Type - PredefinedType: LANDING
Type - ID 데이터 - 유형 이름: 일체형 계단참 150mm_철근콘크리트
Type - 기타 - 카테고리: 계단: 계단참; 패밀리 이름: 일체형 계단참
Type - 디딤판 - 계단진행과 동일: yes
Type - 시공 - 일체형 두께: 150 mm
Type - 재료 및 마감재 - 일체형 재료: KBIMS-콘크리트
Type - Pset_SlabCommon - IsExternal: no
Material: KBIMS-콘크리트
Pset_QuantityTakeOff - Reference: 일체형 계단참 150mm_철근콘크리트; sets with these values: 2
Pset_SlabCommon - PitchAngle: 0 deg; Reference: 일체형 계단참 150mm_철근콘크리트
공정 - 생성 공정: 새 구성
기타 - 유형: 일체형 계단참 150mm_철근콘크리트; 유형 ID: 3060155; 패밀리: 일체형 계단참; 패밀리 및 유형: 일체형 계단참: 일체형 계단참 150mm_철근콘크리트
치수 - 총 두께: 150 mm
Name (현장타설 계단:계단:...) | In | NetArea (m2) | NetVolume (m3) | 상대 높이 (mm)
5314813 Landing 1 | 지상 3층 | 8.53665 | 0.560789 | 2050
5314813 Landing 2 | 지상 3층 | 8.31598 | 0.545142 | 4100
5315106 Landing 1 | 지상 4층 | 8.53665 | 0.560789 | 2050
5315106 Landing 2 | 지상 4층 | 8.31598 | 0.545142 | 4100
5315123 Landing 1 | 지상 5층 | 8.53665 | 0.560789 | 2050
5315123 Landing 2 | 지상 5층 | 8.31598 | 0.545142 | 4100
5315140 Landing 1 | 지상 6층 | 8.53665 | 0.560789 | 2050
5315140 Landing 2 | 지상 6층 | 8.31598 | 0.545142 | 4100
5315157 Landing 1 | 지상 7층 | 8.53665 | 0.560789 | 2050
5315157 Landing 2 | 지상 7층 | 8.31598 | 0.545142 | 4100
5315174 Landing 1 | 지상 8층 | 8.53665 | 0.560789 | 2050
5315174 Landing 2 | 지상 8층 | 8.31598 | 0.545142 | 4100
5315191 Landing 1 | 지상 9층 | 8.28438 | 0.543954 | 2250
5315191 Landing 2 | 지상 9층 | 8.36071 | 0.550581 | 4500
5315208 Landing 1 | 지상 10층 | 9.26771 | 0.612828 | 2500
5315208 Landing 2 | 지상 10층 | 8.43114 | 0.555937 | 5000
5315225 Landing 1 | 지상 3층 | 8.53665 | 0.560789 | 2050
5315225 Landing 2 | 지상 3층 | 8.31598 | 0.545142 | 4100
5315424 Landing 1 | 지상 4층 | 8.53665 | 0.560789 | 2050
5315424 Landing 2 | 지상 4층 | 8.31598 | 0.545142 | 4100
5315439 Landing 1 | 지상 5층 | 8.53665 | 0.560789 | 2050
5315439 Landing 2 | 지상 5층 | 8.31598 | 0.545142 | 4100
5315454 Landing 1 | 지상 6층 | 8.53665 | 0.560789 | 2050
5315454 Landing 2 | 지상 6층 | 8.31598 | 0.545142 | 4100
5315469 Landing 1 | 지상 7층 | 8.53665 | 0.560789 | 2050
5315469 Landing 2 | 지상 7층 | 8.31598 | 0.545142 | 4100
5315484 Landing 1 | 지상 8층 | 8.53665 | 0.560789 | 2050
5315484 Landing 2 | 지상 8층 | 8.31598 | 0.545142 | 4100
5315499 Landing 1 | 지상 9층 | 8.59307 | 0.564405 | 2250
5315499 Landing 2 | 지상 9층 | 8.36607 | 0.549854 | 4500
5948802 Landing 1 | 지상 2층 | 8.57324 | 0.564202 | 2250
5948802 Landing 2 | 지상 2층 | 8.36488 | 0.549748 | 4500
5949467 Landing 1 | 지상 1층 | 4.07708 | 0.260005 | 2400 | BaseQuantities - GrossArea: 0.224144 m2; GrossVolume: 0.260005 m3; Perimeter: 3128.29 mm; Width: 1159.99 mm
5949467 Landing 2 | 지상 1층 | 4.26803 | 0.274313 | 2769.23
5949467 Landing 3 | 지상 1층 | 9.89535 | 0.657045 | 4800
5957725 Landing 1 | 지하2층 | 9.44123 | 0.626676 | 1990.48
5957725 Landing 2 | 지하2층 | 4.40068 | 0.283613 | 3980.95 | BaseQuantities - GrossArea: 0.22838 m2; GrossVolume: 0.283613 m3; Perimeter: 3175.85 mm; Width: 1241.85 mm
5959476 Landing 1 | 지상 2층 | 8.57324 | 0.564202 | 2250
5959476 Landing 2 | 지상 2층 | 8.36488 | 0.549748 | 4500
5959493 Landing 1 | 지상 1층 | 4.75828 | 0.305245 | 2400 | BaseQuantities - GrossArea: 0.263144 m2; GrossVolume: 0.305245 m3; Perimeter: 3648.29 mm; Width: 1159.99 mm
5959493 Landing 2 | 지상 1층 | 5.03035 | 0.328763 | 2769.23
5959493 Landing 3 | 지상 1층 | 8.46439 | 0.555573 | 4800
5961117 Landing 1 | 지하1층 | 4.04784 | 0.261583 | 406.667
5961117 Landing 2 | 지하1층 | 3.89379 | 0.246192 | 2846.67
5961117 Landing 3 | 지하1층 | 3.85163 | 0.246836 | 3456.67
5961117 Landing 4 | 지하1층 | 7.19624 | 0.464897 | 6100
6014588 Landing 1 | 지상 10층 | 3.90573 | 0.24831 | 2222.22
6014588 Landing 2 | 지상 10층 | 3.32111 | 0.208355 | 2592.59
6014588 Landing 3 | 지상 10층 | 8.09863 | 0.530047 | 5000

# IfcStair: 현장타설 계단:ST111-철근콘크리트구조 계단 (U형) (22)
Pset_QuantityTakeOff - Reference: ST111-철근콘크리트구조 계단 (U형)
Pset_StairCommon - IsExternal: no; Reference: ST111-철근콘크리트구조 계단 (U형)
공정 - 생성 공정: 새 구성
구조 - 보강 철근 피복: 보강 철근 피복 1 <25 mm>
기타 - 카테고리: 계단; 패밀리: 현장타설 계단; 유형: ST111-철근콘크리트구조 계단 (U형); 유형 ID: 3060157; 패밀리 및 유형: 현장타설 계단: ST111-철근콘크리트구조 계단 (U형)
치수 - 디딤판/챌판 시작 번호: 1
ID 데이터(Type) - 단가: 0; 유형 이름: ST111-철근콘크리트구조 계단 (U형)
계산 규칙(Type) - 최대 챌판 높이: 190 mm; 최소 계단진행 폭: 1000 mm; 최소 디딤판 깊이: 270 mm
그래픽(Type) - 절단 마크 유형: @단일 지그재그
기타(Type) - 내화구조여부: yes; 주요구조부여부: yes; 카테고리: 계단; KBIMS-부위코드: E270; 조달청표준공사코드: AD; 패밀리 이름: 현장타설 계단; 피난계단여부: yes
시공(Type) - 기능: 내부; 계단진행 유형: 일체형 계단진행 150mm_철근콘크리트; 계단참 유형: 일체형 계단참 150mm_철근콘크리트
지지(Type) - 오른쪽 지지: 없음; 오른쪽 횡력 간격띄우기: 0 mm; 왼쪽 지지: 없음; 왼쪽 횡력 간격띄우기: 0 mm; 중간 지지: no; 중간 지지 번호: 0
Name (현장타설 계단:계단:...) | In | NumberOfRiser = 챌판의 실제 수 | NumberOfTreads | RiserHeight (mm) = 실제 챌판 높이 (mm) | TreadLength (mm) = 실제 디딤판 깊이 (mm) | 상단 간격띄우기 (mm) | 베이스 간격띄우기 (mm) | 베이스 레벨 | 상단 레벨 | 원하는 계단 높이 (mm) | 원하는 챌판 수
5314813 | 지상 3층 | 24 | 22 | 170.833 | 260 | 0 | -0.00000112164 | 지상 3층 | 지상 4층 | 4100 | 24
5315106 | 지상 4층 | 24 | 22 | 170.833 | 260 | 0.00000111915 | 0 | 지상 4층 | 지상 5층 | 4100 | 24
5315123 | 지상 5층 | 24 | 22 | 170.833 | 260 | 0 | -0.00000112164 | 지상 5층 | 지상 6층 | 4100 | 24
5315140 | 지상 6층 | 24 | 22 | 170.833 | 260 | 0 | -0.00000112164 | 지상 6층 | 지상 7층 | 4100 | 24
5315157 | 지상 7층 | 24 | 22 | 170.833 | 260 | 0 | -0.00000112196 | 지상 7층 | 지상 8층 | 4100 | 24
5315174 | 지상 8층 | 24 | 22 | 170.833 | 260 | 0 | -0.00000112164 | 지상 8층 | 지상 9층 | 4100 | 24
5315191 | 지상 9층 | 24 | 22 | 187.5 | 270 | -0.00000112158 | -0.00000112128 | 지상 9층 | 지상 10층 | 4500 | 24
5315208 | 지상 10층 | 24 | 22 | 208.333 | 260 | -0.00000112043 | -0.00000112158 | 지상 10층 | 옥탑층 | 5000 | 24
5315225 | 지상 3층 | 24 | 22 | 170.833 | 260 | 0 | -0.00000112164 | 지상 3층 | 지상 4층 | 4100 | 24
5315424 | 지상 4층 | 24 | 22 | 170.833 | 260 | 0.00000111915 | 0 | 지상 4층 | 지상 5층 | 4100 | 24
5315439 | 지상 5층 | 24 | 22 | 170.833 | 260 | 0 | -0.00000112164 | 지상 5층 | 지상 6층 | 4100 | 24
5315454 | 지상 6층 | 24 | 22 | 170.833 | 260 | 0 | -0.00000112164 | 지상 6층 | 지상 7층 | 4100 | 24
5315469 | 지상 7층 | 24 | 22 | 170.833 | 260 | 0 | -0.00000112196 | 지상 7층 | 지상 8층 | 4100 | 24
5315484 | 지상 8층 | 24 | 22 | 170.833 | 260 | 0 | -0.00000112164 | 지상 8층 | 지상 9층 | 4100 | 24
5315499 | 지상 9층 | 24 | 22 | 187.5 | 260 | -0.00000112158 | -0.00000112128 | 지상 9층 | 지상 10층 | 4500 | 24
5948802 | 지상 2층 | 24 | 22 | 187.5 | 260 | 0 | 0 | 지상 2층 | 지상 3층 | 4500 | 24
5949467 | 지상 1층 | 26 | 23 | 184.615 | 260 | 0 | 0 | 지상 1층 | 지상 2층 | 4800 | 26
5957725 | 지하2층 | 22 | 20 | 180.952 | 270 | 0 | 200 | 지하2층 | 지하1층 | 3800 | 21
5959476 | 지상 2층 | 24 | 22 | 187.5 | 260 | 0 | 0 | 지상 2층 | 지상 3층 | 4500 | 24
5959493 | 지상 1층 | 26 | 23 | 184.615 | 260 | 0 | 0 | 지상 1층 | 지상 2층 | 4800 | 26
5961117 | 지하1층 | 30 | 26 | 203.333 | 260 | 0 | 0 | 지하1층 | 지상 1층 | 6100 | 30
6014588 | 지상 10층 | 27 | 24 | 185.185 | 270 | 0 | 0 | 지상 10층 | 옥탑층 | 5000 | 27

# IfcStair: 현장타설 계단:ST111-철근콘크리트구조 계단 (직선형) (4)
ShapeType: STRAIGHT_RUN_STAIR
Pset_QuantityTakeOff - Reference: ST111-철근콘크리트구조 계단 (직선형)
Pset_StairCommon - IsExternal: no; Reference: ST111-철근콘크리트구조 계단 (직선형)
공정 - 생성 공정: 새 구성
구조 - 보강 철근 피복: 보강 철근 피복 1 <25 mm>
기타 - 유형: ST111-철근콘크리트구조 계단 (직선형); 유형 ID: 7468661; 카테고리: 계단; 패밀리: 현장타설 계단; 패밀리 및 유형: 현장타설 계단: ST111-철근콘크리트구조 계단 (직선형)
치수 - 디딤판/챌판 시작 번호: 1
ID 데이터(Type) - 단가: 0; 유형 이름: ST111-철근콘크리트구조 계단 (직선형)
계산 규칙(Type) - 최대 챌판 높이: 190 mm; 최소 계단진행 폭: 1000 mm; 최소 디딤판 깊이: 270 mm
그래픽(Type) - 절단 마크 유형: @단일 지그재그
기타(Type) - 카테고리: 계단; KBIMS-부위코드: E270; 내화구조여부: no; 조달청표준공사코드: AD; 주요구조부여부: no; 패밀리 이름: 현장타설 계단; 피난계단여부: no
시공(Type) - 기능: 내부; 계단진행 유형: 일체형 계단진행 150mm_철근콘크리트; 계단참 유형: 일체형 계단참 150mm_철근콘크리트
지지(Type) - 오른쪽 지지: 없음; 오른쪽 횡력 간격띄우기: 0 mm; 왼쪽 지지: 없음; 왼쪽 횡력 간격띄우기: 0 mm; 중간 지지: no; 중간 지지 번호: 0
Name (현장타설 계단:계단:...) | In | NumberOfRiser = 원하는 챌판 수 = 챌판의 실제 수 | NumberOfTreads | RiserHeight (mm) = 실제 챌판 높이 (mm) | TreadLength (mm) = 실제 디딤판 깊이 (mm) | 베이스 간격띄우기 (mm) | 상단 간격띄우기 (mm) | 베이스 레벨 | 상단 레벨 | 원하는 계단 높이 (mm)
3159392 | 지하2층 | 10 | 9 | 180 | 270 | 0 | 0 | PIT | 지하2층 | 1800
5367392 | 지상 1층 | 6 | 5 | 166.667 | 296.667 | -1500 | -500 | 지상 1층 | 지상 1층 | 1000
5367428 | 지상 1층 | 4 | 3 | 150 | 330 | -2100 | -1500 | 지상 1층 | 지상 1층 | 600
5367435 | 지상 1층 | 3 | 2 | 166.667 | 296.667 | -500 | 0 | 지상 1층 | 지상 1층 | 500

# IfcStairFlight: 일체형 계단진행:일체형 계단진행 150mm_철근콘크리트 (52)
Type - PredefinedType: STRAIGHT
Type - ID 데이터 - 유형 이름: 일체형 계단진행 150mm_철근콘크리트
Type - 기타 - 카테고리: 계단: 계단진행; 패밀리 이름: 일체형 계단진행
Type - 디딤판 - 계단코 길이: 0 mm; 계단코 프로파일 적용: 앞쪽만; 디딤판: no; 디딤판 두께: 0 mm
Type - 시공 - 구조 깊이: 150 mm; 밑면 표면: 매끄러움
Type - 재료 및 마감재 - 디딤판 재료: KBIMS-콘크리트; 일체형 재료: KBIMS-콘크리트; 챌판 재료: KBIMS-콘크리트
Type - 챌판 - 경사: no; 챌판: no; 챌판과 디딤판 간의 연결: 디딤판 뒤쪽으로 챌판 확장; 챌판 두께: 0 mm
Material: KBIMS-콘크리트
Pset_QuantityTakeOff - Reference: 일체형 계단진행 150mm_철근콘크리트
Pset_StairFlightCommon - Reference: 일체형 계단진행 150mm_철근콘크리트; NosingLength: 0 mm
공정 - 생성 공정: 새 구성
기타 - 유형: 일체형 계단진행 150mm_철근콘크리트; 유형 ID: 3060156; 패밀리: 일체형 계단진행; 패밀리 및 유형: 일체형 계단진행: 일체형 계단진행 150mm_철근콘크리트
시공 - 챌판으로 끝남: yes; 챌판으로 시작함: yes
Name (현장타설 계단:계단:...) | In | NumberOfRiser = Pset_StairFlightCommon, NumberOfRiser = 챌판의 실제 수 | NumberOfTreads = Pset_StairFlightCommon, NumberOfTreads = 실제 디딤판 개수 | RiserHeight (mm) | TreadLength (mm) | Pset_StairFlightCommon, RiserHeight (mm) = 실제 챌판 높이 (mm) | Pset_StairFlightCommon, TreadLength (mm) = TreadLengthAtOffset (mm) = TreadLengthAtInnerSide (mm) = 실제 디딤판 깊이 (mm) | WalkingLineOffset (mm) | NetVolume (m3) | Length (mm) | 관련 기준 높이 (mm) | 계단진행 높이 (mm) | 상대 상단 높이 (mm) | 위치선 | 실제 계단진행 폭 (mm)
5314813 Run 1 | 지상 3층 | 12 | 11 | 0.560477 | 0.853018 | 170.833 | 260 | 2.05054 | 0.946191 | 2860 | 0 | 2050 | 2050 | 계단진행: 중심 | 1250.01 | 시공 - 챌판 베이스 아래로 확장: -150 mm
5314813 Run 2 | 지상 3층 | 12 | 11 | 0.560477 | 0.853018 | 170.833 | 260 | 2.05052 | 0.946184 | 2860 | 2050 | 2050 | 4100 | 계단진행: 중심 | 1250
5315106 Run 1 | 지상 4층 | 12 | 11 | 0.560477 | 0.853018 | 170.833 | 260 | 2.05054 | 0.946191 | 2860 | 0 | 2050 | 2050 | 계단진행: 중심 | 1250.01 | 시공 - 챌판 베이스 아래로 확장: -150 mm
5315106 Run 2 | 지상 4층 | 12 | 11 | 0.560477 | 0.853018 | 170.833 | 260 | 2.05052 | 0.946184 | 2860 | 2050 | 2050 | 4100 | 계단진행: 중심 | 1250
5315123 Run 1 | 지상 5층 | 12 | 11 | 0.560477 | 0.853018 | 170.833 | 260 | 2.05054 | 0.946191 | 2860 | 0 | 2050 | 2050 | 계단진행: 중심 | 1250.01 | 시공 - 챌판 베이스 아래로 확장: -150 mm
5315123 Run 2 | 지상 5층 | 12 | 11 | 0.560477 | 0.853018 | 170.833 | 260 | 2.05052 | 0.946184 | 2860 | 2050 | 2050 | 4100 | 계단진행: 중심 | 1250
5315140 Run 1 | 지상 6층 | 12 | 11 | 0.560477 | 0.853018 | 170.833 | 260 | 2.05054 | 0.946191 | 2860 | 0 | 2050 | 2050 | 계단진행: 중심 | 1250.01 | 시공 - 챌판 베이스 아래로 확장: -150 mm
5315140 Run 2 | 지상 6층 | 12 | 11 | 0.560477 | 0.853018 | 170.833 | 260 | 2.05052 | 0.946184 | 2860 | 2050 | 2050 | 4100 | 계단진행: 중심 | 1250
5315157 Run 1 | 지상 7층 | 12 | 11 | 0.560477 | 0.853018 | 170.833 | 260 | 2.05054 | 0.946191 | 2860 | 0 | 2050 | 2050 | 계단진행: 중심 | 1250.01 | 시공 - 챌판 베이스 아래로 확장: -150 mm
5315157 Run 2 | 지상 7층 | 12 | 11 | 0.560477 | 0.853018 | 170.833 | 260 | 2.05052 | 0.946184 | 2860 | 2050 | 2050 | 4100 | 계단진행: 중심 | 1250
5315174 Run 1 | 지상 8층 | 12 | 11 | 0.560477 | 0.853018 | 170.833 | 260 | 2.05054 | 0.946191 | 2860 | 0 | 2050 | 2050 | 계단진행: 중심 | 1250.01 | 시공 - 챌판 베이스 아래로 확장: -150 mm
5315174 Run 2 | 지상 8층 | 12 | 11 | 0.560477 | 0.853018 | 170.833 | 260 | 2.05052 | 0.946184 | 2860 | 2050 | 2050 | 4100 | 계단진행: 중심 | 1250
5315191 Run 1 | 지상 9층 | 12 | 11 | 0.615157 | 0.885827 | 187.5 | 270 | 2.05054 | 1.02508 | 2970 | 0 | 2250 | 2250 | 계단진행: 중심 | 1250.01 | 시공 - 챌판 베이스 아래로 확장: -150 mm
5315191 Run 2 | 지상 9층 | 12 | 11 | 0.615157 | 0.885827 | 187.5 | 270 | 2.05052 | 1.02507 | 2970 | 2250 | 2250 | 4500 | 계단진행: 중심 | 1250
5315208 Run 1 | 지상 10층 | 12 | 11 | 0.683508 | 0.853018 | 208.333 | 260 | 2.05054 | 1.05818 | 2860 | 0 | 2500 | 2500 | 계단진행: 중심 | 1250.01 | 시공 - 챌판 베이스 아래로 확장: -150 mm
5315208 Run 2 | 지상 10층 | 12 | 11 | 0.683508 | 0.853018 | 208.333 | 260 | 2.05052 | 1.05817 | 2860 | 2500 | 2500 | 5000 | 계단진행: 중심 | 1250
5315225 Run 1 | 지상 3층 | 12 | 11 | 0.560477 | 0.853018 | 170.833 | 260 | 2.05054 | 0.946191 | 2860 | 0 | 2050 | 2050 | 계단진행: 중심 | 1250.01 | 시공 - 챌판 베이스 아래로 확장: -150 mm
5315225 Run 2 | 지상 3층 | 12 | 11 | 0.560477 | 0.853018 | 170.833 | 260 | 2.05052 | 0.946184 | 2860 | 2050 | 2050 | 4100 | 계단진행: 중심 | 1250
5315424 Run 1 | 지상 4층 | 12 | 11 | 0.560477 | 0.853018 | 170.833 | 260 | 2.05054 | 0.946191 | 2860 | 0 | 2050 | 2050 | 계단진행: 중심 | 1250.01 | 시공 - 챌판 베이스 아래로 확장: -150 mm
5315424 Run 2 | 지상 4층 | 12 | 11 | 0.560477 | 0.853018 | 170.833 | 260 | 2.05052 | 0.946184 | 2860 | 2050 | 2050 | 4100 | 계단진행: 중심 | 1250
5315439 Run 1 | 지상 5층 | 12 | 11 | 0.560477 | 0.853018 | 170.833 | 260 | 2.05054 | 0.946191 | 2860 | 0 | 2050 | 2050 | 계단진행: 중심 | 1250.01 | 시공 - 챌판 베이스 아래로 확장: -150 mm
5315439 Run 2 | 지상 5층 | 12 | 11 | 0.560477 | 0.853018 | 170.833 | 260 | 2.05052 | 0.946184 | 2860 | 2050 | 2050 | 4100 | 계단진행: 중심 | 1250
5315454 Run 1 | 지상 6층 | 12 | 11 | 0.560477 | 0.853018 | 170.833 | 260 | 2.05054 | 0.946191 | 2860 | 0 | 2050 | 2050 | 계단진행: 중심 | 1250.01 | 시공 - 챌판 베이스 아래로 확장: -150 mm
5315454 Run 2 | 지상 6층 | 12 | 11 | 0.560477 | 0.853018 | 170.833 | 260 | 2.05052 | 0.946184 | 2860 | 2050 | 2050 | 4100 | 계단진행: 중심 | 1250
5315469 Run 1 | 지상 7층 | 12 | 11 | 0.560477 | 0.853018 | 170.833 | 260 | 2.05054 | 0.946191 | 2860 | 0 | 2050 | 2050 | 계단진행: 중심 | 1250.01 | 시공 - 챌판 베이스 아래로 확장: -150 mm
5315469 Run 2 | 지상 7층 | 12 | 11 | 0.560477 | 0.853018 | 170.833 | 260 | 2.05052 | 0.946184 | 2860 | 2050 | 2050 | 4100 | 계단진행: 중심 | 1250
5315484 Run 1 | 지상 8층 | 12 | 11 | 0.560477 | 0.853018 | 170.833 | 260 | 2.05054 | 0.946191 | 2860 | 0 | 2050 | 2050 | 계단진행: 중심 | 1250.01 | 시공 - 챌판 베이스 아래로 확장: -150 mm
5315484 Run 2 | 지상 8층 | 12 | 11 | 0.560477 | 0.853018 | 170.833 | 260 | 2.05052 | 0.946184 | 2860 | 2050 | 2050 | 4100 | 계단진행: 중심 | 1250
5315499 Run 1 | 지상 9층 | 12 | 11 | 0.615157 | 0.853018 | 187.5 | 260 | 2.05054 | 0.995253 | 2860 | 0 | 2250 | 2250 | 계단진행: 중심 | 1250.01 | 시공 - 챌판 베이스 아래로 확장: -150 mm
5315499 Run 2 | 지상 9층 | 12 | 11 | 0.615157 | 0.853018 | 187.5 | 260 | 2.05052 | 0.995245 | 2860 | 2250 | 2250 | 4500 | 계단진행: 중심 | 1250
5367392 Run 1 | 지상 1층 | 6 | 5 | 0.546807 | 0.973316 | 166.667 | 296.667 | 2.62469 | 0.606115 | 1483.33 | 0 | 1000 | 1000 | 계단진행: 중심 | 1600.01 | 시공 - 챌판 베이스 아래로 확장: -200 mm
5367428 Run 1 | 지상 1층 | 4 | 3 | 0.492126 | 1.08268 | 150 | 330 | 2.62469 | 0.379796 | 990 | 0 | 600 | 600 | 계단진행: 중심 | 1600.01 | 시공 - 챌판 베이스 아래로 확장: -200 mm
5367435 Run 1 | 지상 1층 | 3 | 2 | 0.546807 | 0.973316 | 166.667 | 296.667 | 2.62469 | 0.242446 | 593.333 | 0 | 500 | 500 | 계단진행: 중심 | 1600.01 | 시공 - 챌판 베이스 아래로 확장: -200 mm
5948802 Run 1 | 지상 2층 | 12 | 11 | 0.615157 | 0.853018 | 187.5 | 260 | 2.00647 | 0.945895 | 2860 | 0 | 2250 | 2250 | 계단진행: 오른쪽 | 1223.15 | 시공 - 챌판 베이스 아래로 확장: 0 mm
5948802 Run 2 | 지상 2층 | 12 | 11 | 0.615157 | 0.853018 | 187.5 | 260 | 2.04751 | 0.993782 | 2860 | 2250 | 2250 | 4500 | 계단진행: 오른쪽 | 1248.16
5949467 Run 1 | 지상 1층 | 13 | 12 | 0.605694 | 0.853018 | 184.615 | 260 | 1.90287 | 0.972245 | 3120 | 0 | 2400 | 2400 | 계단진행: 오른쪽 | 1159.99 | 시공 - 챌판 베이스 아래로 확장: 0 mm
5949467 Run 2 | 지상 1층 | 2 | 1 | 0.605694 | 0.853018 | 184.615 | 260 | 2.08333 | 0.0901943 | 260 | 2400 | 369.231 | 2769.23 | 계단진행: 오른쪽 | 1270 | BaseQuantities - GrossVolume: 0.0901943 m3
5949467 Run 3 | 지상 1층 | 11 | 10 | 0.605694 | 0.853018 | 184.615 | 260 | 1.92233 | 0.84081 | 2600 | 2769.23 | 2030.77 | 4800 | 계단진행: 오른쪽 | 1171.85
5957725 Run 1 | 지하2층 | 11 | 10 | 0.593676 | 0.885827 | 180.952 | 270 | 2.04757 | 0.883105 | 2700 | 0 | 1990.48 | 1990.48 | 계단진행: 오른쪽 | 1248.2 | 시공 - 챌판 베이스 아래로 확장: 0 mm
5957725 Run 2 | 지하2층 | 11 | 10 | 0.593676 | 0.885827 | 180.952 | 270 | 2.05355 | 0.915265 | 2700 | 1990.48 | 1990.48 | 3980.95 | 계단진행: 오른쪽 | 1251.85
5959476 Run 1 | 지상 2층 | 12 | 11 | 0.615157 | 0.853018 | 187.5 | 260 | 2.00647 | 0.945895 | 2860 | 0 | 2250 | 2250 | 계단진행: 오른쪽 | 1223.15 | 시공 - 챌판 베이스 아래로 확장: 0 mm
5959476 Run 2 | 지상 2층 | 12 | 11 | 0.615157 | 0.853018 | 187.5 | 260 | 2.04751 | 0.993782 | 2860 | 2250 | 2250 | 4500 | 계단진행: 오른쪽 | 1248.16
5959493 Run 1 | 지상 1층 | 13 | 12 | 0.605694 | 0.853018 | 184.615 | 260 | 1.90287 | 0.972245 | 3120 | 0 | 2400 | 2400 | 계단진행: 오른쪽 | 1159.99 | 시공 - 챌판 베이스 아래로 확장: 0 mm
5959493 Run 2 | 지상 1층 | 2 | 1 | 0.605694 | 0.853018 | 184.615 | 260 | 2.50984 | 0.108659 | 260 | 2400 | 369.231 | 2769.23 | 계단진행: 오른쪽 | 1530 | BaseQuantities - GrossVolume: 0.108659 m3
5959493 Run 3 | 지상 1층 | 11 | 10 | 0.605694 | 0.853018 | 184.615 | 260 | 1.92233 | 0.84081 | 2600 | 2769.23 | 2030.77 | 4800 | 계단진행: 오른쪽 | 1171.85
5961117 Run 1 | 지하1층 | 2 | 1 | 0.667104 | 0.853018 | 203.333 | 260 | 2.13249 | 0.0685863 | 260 | 0 | 406.667 | 406.667 | 계단진행: 오른쪽 | 1299.97 | 시공 - 챌판 베이스 아래로 확장: 0 mm; BaseQuantities - GrossVolume: 0.0685863 m3
5961117 Run 2 | 지하1층 | 12 | 11 | 0.667104 | 0.853018 | 203.333 | 260 | 1.64042 | 0.834333 | 2860 | 406.667 | 2440 | 2846.67 | 계단진행: 오른쪽 | 1000
5961117 Run 3 | 지하1층 | 3 | 2 | 0.667104 | 0.853018 | 203.333 | 260 | 1.9685 | 0.181011 | 520 | 2846.67 | 610 | 3456.67 | 계단진행: 오른쪽 | 1200
5961117 Run 4 | 지하1층 | 13 | 12 | 0.667104 | 0.853018 | 203.333 | 260 | 1.70608 | 0.946709 | 3120 | 3456.67 | 2643.33 | 6100 | 계단진행: 오른쪽 | 1040.02
6014588 Run 1 | 지상 10층 | 12 | 11 | 0.607563 | 0.885827 | 185.185 | 270 | 1.78806 | 0.862297 | 2970 | 0 | 2222.22 | 2222.22 | 계단진행: 오른쪽 | 1090 | 시공 - 챌판 베이스 아래로 확장: 0 mm
6014588 Run 2 | 지상 10층 | 2 | 1 | 0.607563 | 0.885827 | 185.185 | 270 | 1.64042 | 0.0733692 | 270 | 2222.22 | 370.37 | 2592.59 | 계단진행: 오른쪽 | 1000 | BaseQuantities - GrossVolume: 0.0733692 m3
6014588 Run 3 | 지상 10층 | 13 | 12 | 0.607563 | 0.885827 | 185.185 | 270 | 1.84553 | 0.999691 | 3240 | 2592.59 | 2407.41 | 5000 | 계단진행: 오른쪽 | 1125.03

# IfcStairFlight: 일체형 계단진행:일체형 계단진행 150mm_철근콘크리트, 현장타설 계단:계단:3159392 Run 1
In: 지하2층
Type - ID 데이터 - 유형 이름: 일체형 계단진행 150mm_철근콘크리트
Type - 기타 - 카테고리: 계단: 계단진행; 패밀리 이름: 일체형 계단진행
Type - 디딤판 - 계단코 길이: 0 mm; 계단코 프로파일 적용: 앞쪽만; 디딤판: no; 디딤판 두께: 0 mm
Type - 시공 - 구조 깊이: 150 mm; 밑면 표면: 매끄러움
Type - 재료 및 마감재 - 디딤판 재료: KBIMS-콘크리트; 일체형 재료: KBIMS-콘크리트; 챌판 재료: KBIMS-콘크리트
Type - 챌판 - 경사: no; 챌판: no; 챌판과 디딤판 간의 연결: 디딤판 뒤쪽으로 챌판 확장; 챌판 두께: 0 mm
NumberOfRiser: 10; NumberOfTreads: 9; RiserHeight: 0.590551 mm; TreadLength: 0.885827 mm; Material: KBIMS-콘크리트
Pset_QuantityTakeOff - Reference: 일체형 계단진행 150mm_철근콘크리트
Pset_StairFlightCommon - Reference: 일체형 계단진행 150mm_철근콘크리트; NumberOfRiser: 10; NumberOfTreads: 9; RiserHeight: 180 mm; TreadLength: 270 mm; NosingLength: 0 mm; TreadLengthAtOffset: 270 mm; TreadLengthAtInnerSide: 270 mm
BaseQuantities - NetVolume: 0.368081 m3; Length: 2340 mm
공정 - 생성 공정: 새 구성
구속조건 - 계단진행 높이: 1800 mm; 관련 기준 높이: 0 mm; 상대 상단 높이: 1800 mm
기타 - 유형: 일체형 계단진행 150mm_철근콘크리트; 유형 ID: 3060156; 패밀리: 일체형 계단진행; 패밀리 및 유형: 일체형 계단진행: 일체형 계단진행 150mm_철근콘크리트
시공 - 챌판 베이스 아래로 확장: 0 mm; 챌판으로 끝남: yes; 챌판으로 시작함: yes
치수 - 챌판의 실제 수: 10; 실제 디딤판 개수: 9; 실제 챌판 높이: 180 mm

# IfcSystem: Return Air (15)
기계 - 흐름 - 유량: 0 m3/s
기타 - 카테고리: 덕트 시스템; 패밀리: 덕트 시스템; 유형: Return Air; 유형 ID: 7855751; 패밀리 및 유형: 덕트 시스템: Return Air
Name | 요소 수 | 시스템 이름
기계 Return Air 1 | 0 | 기계 Return Air 1
기계 Return Air 6 | 1 | 기계 Return Air 6
기계 Return Air 2 | 0 | 기계 Return Air 2 | 기계 - 정압: 0 Pa
기계 Return Air 3 | 0 | 기계 Return Air 3 | 기계 - 정압: 0 Pa
기계 Return Air 7 | 1 | 기계 Return Air 7 | 기계 - 정압: 0 Pa
기계 Return Air 8 | 1 | 기계 Return Air 8 | 기계 - 정압: 0 Pa
기계 Return Air 14 | 0 | 기계 Return Air 14
기계 Return Air 16 | 0 | 기계 Return Air 16
기계 Return Air 18 | 0 | 기계 Return Air 18
기계 Return Air 20 | 0 | 기계 Return Air 20
기계 Return Air 22 | 0 | 기계 Return Air 22
기계 Return Air 24 | 0 | 기계 Return Air 24
기계 Return Air 26 | 0 | 기계 Return Air 26
기계 Return Air 28 | 0 | 기계 Return Air 28
기계 Return Air 30 | 0 | 기계 Return Air 30

# IfcSystem: Supply Air (8)
기계 - 요소 수: 0
기계 - 흐름 - 유량: 0 m3/s
기타 - 유형: Supply Air; 유형 ID: 7855750; 카테고리: 덕트 시스템; 패밀리: 덕트 시스템; 패밀리 및 유형: 덕트 시스템: Supply Air
Name | 시스템 이름
기계 Supply Air 1 | 기계 Supply Air 1 | 기계 - 정압: 0 Pa
기계 Supply Air 2 | 기계 Supply Air 2 | 기계 - 정압: 0 Pa
기계 Supply Air 4 | 기계 Supply Air 4
기계 Supply Air 6 | 기계 Supply Air 6
기계 Supply Air 8 | 기계 Supply Air 8
기계 Supply Air 10 | 기계 Supply Air 10
기계 Supply Air 12 | 기계 Supply Air 12
기계 Supply Air 14 | 기계 Supply Air 14

# IfcWall: 기본 벽:(복합)A1-32-06A+WA111+A1-33-01B_수성+철콘+화장실 (3)
In: 지상 10층
Type - PredefinedType: STANDARD; Material: WA611-수성페인트 (내부) 벽 (3회) 1 mm, WA551-시멘트모르타르 (내부) 벽 18mm 16 mm, WA555-콘크리트면정리 벽 (내부) 1 mm, KBIMS-콘크리트 200 mm, WA551-시멘트모르타르 (내부) 벽 18mm 22 mm, WA352-도기질타일 벽 200x200 8 mm
Type - ID 데이터 - 단가: 0; 유형 마크: CW1; 유형 이름: (복합)A1-32-06A+WA111+A1-33-01B_수성+철콘+화장실
Type - 그래픽 - 거친 축척 채우기 색상: 0
Type - 기타 - 내화구조여부: yes; 주요구조부여부: yes; 카테고리: 벽; KBIMS-부위코드: E275; 조달청표준공사코드: ADANC132110000+AGA113100000+AGA441100000+AMA112C+AGA114400000; 패밀리 이름: 기본 벽
Type - 시공 - 기능: 외부; 끝단부 마무리: 없음; 인서트 부위 마무리: 마무리하지 않음; 폭: 248 mm
Type - 재료 및 마감재 - 구조 재료: KBIMS-콘크리트
Type - 해석 특성 - 거칠기: 1; 열 저항(R): 0.245707; 열 전달 계수(U): 4.0699 kg/K/s3; 열 질량: 364.08; 흡수율: 9290.3
Type - Pset_WallCommon - IsExternal: yes; ThermalTransmittance: 4.0699 kg/K/s3
공정 - 생성 공정: 새 구성
구속조건 - 베이스 간격띄우기: 0 mm; 매스와 관련됨: no; 룸 경계: yes; 베이스 확장 거리: 0 mm; 벽 베이스가 부착됩니다.: no; 상단 간격띄우기: 0 mm; 상단 확장 거리: 0 mm; 상단이 부착됩니다.: no; 위치선: 구조체 면:외부; 베이스 구속조건: 지상 10층; 상단 구속조건: 상위 레벨: 옥탑층; 미연결 높이: 5000 mm
구조 - 구조: yes; 보강 철근 피복 - 다른 면: 보강 철근 피복 1 <25 mm>; 구조적 용도: 교좌장치; 보강 철근 피복 - 내부 면: 보강 철근 피복 1 <25 mm>; 보강 철근 피복 - 외부 면: 보강 철근 피복 1 <25 mm>
기타 - 패밀리: 기본 벽; 유형: (복합)A1-32-06A+WA111+A1-33-01B_수성+철콘+화장실; 유형 ID: 7717586; 패밀리 및 유형: 기본 벽: (복합)A1-32-06A+WA111+A1-33-01B_수성+철콘+화장실
단면형상 정의 - 단면형상: 수직
Pset_QuantityTakeOff - Reference: (복합)A1-32-06A+WA111+A1-33-01B_수성+철콘+화장실; sets with these values: 2
Pset_WallCommon - LoadBearing: yes; ExtendToStructure: no; Reference: (복합)A1-32-06A+WA111+A1-33-01B_수성+철콘+화장실
Name (기본 벽:(복합)A1-32-06A+WA111+A1-33-01B_수성+철콘+화장실:...) | 연관 있음 | 길이 (mm) | 면적 (m2) | 체적 (m3)
2822423 | yes | 4379 | 18.5367 | 4.51678
7719927 | no | 2500.98 | 11.5575 | 2.85903
7720241 | no | 4396 | 19.8574 | 4.88403

# IfcWall: 기본 벽:(복합)A2-22-02A+WA111(200_CW1)+A1-33-01B_압출+철콘+화장실, 기본 벽:(복합)A2-22-02A+WA111(200_CW1)+A1-33-01B_압출+철콘+화장실:7720721
In: 지상 10층
Type - PredefinedType: STANDARD; Material: WA240-ALC블록벽 35 mm, WA795-(STEEL)BRACKET 65 mm, WA821-압출스티로폼 벽 (본드붙임, 비중0.03) 50mm 50 mm, KBIMS-콘크리트 200 mm, WA551-시멘트모르타르 (내부) 벽 18mm 22 mm, WA352-도기질타일 벽 200x200 8 mm
Type - ID 데이터 - 단가: 0; 유형 마크: CW1; 유형 이름: (복합)A2-22-02A+WA111(200_CW1)+A1-33-01B_압출+철콘+화장실
Type - 그래픽 - 거친 축척 채우기 색상: 0
Type - 기타 - 내화구조여부: yes; 주요구조부여부: yes; 카테고리: 벽; KBIMS-부위코드: E275; 조달청표준공사코드: AFC100+AJM+AOD112322000+AD+ANC132110000+AGA113100000+AGA441100000; 패밀리 이름: 기본 벽
Type - 시공 - 기능: 외부; 끝단부 마무리: 없음; 인서트 부위 마무리: 마무리하지 않음; 폭: 380 mm
Type - 재료 및 마감재 - 구조 재료: KBIMS-콘크리트
Type - 해석 특성 - 거칠기: 1; 열 저항(R): 2.07361; 열 전달 계수(U): 0.48225 kg/K/s3; 열 질량: 338.188; 흡수율: 9290.3
Type - Pset_WallCommon - IsExternal: yes; ThermalTransmittance: 0.48225 kg/K/s3
ID 데이터 - 연관 있음: no
공정 - 생성 공정: 새 구성
구속조건 - 베이스 간격띄우기: 0 mm; 매스와 관련됨: no; 룸 경계: yes; 베이스 확장 거리: 0 mm; 벽 베이스가 부착됩니다.: no; 상단 간격띄우기: 0 mm; 상단 확장 거리: 0 mm; 상단이 부착됩니다.: no; 위치선: 구조체 면:외부; 베이스 구속조건: 지상 10층; 상단 구속조건: 상위 레벨: 옥탑층; 미연결 높이: 5000 mm
구조 - 구조: yes; 보강 철근 피복 - 다른 면: 보강 철근 피복 1 <25 mm>; 구조적 용도: 교좌장치; 보강 철근 피복 - 내부 면: 보강 철근 피복 1 <25 mm>; 보강 철근 피복 - 외부 면: 보강 철근 피복 1 <25 mm>
기타 - 패밀리: 기본 벽; 유형: (복합)A2-22-02A+WA111(200_CW1)+A1-33-01B_압출+철콘+화장실; 유형 ID: 7717582; 패밀리 및 유형: 기본 벽: (복합)A2-22-02A+WA111(200_CW1)+A1-33-01B_압출+철콘+화장실
단면형상 정의 - 단면형상: 수직
치수 - 길이: 3421.99 mm; 면적: 16.925 m2; 체적: 6.42522 m3
Pset_QuantityTakeOff - Reference: (복합)A2-22-02A+WA111(200_CW1)+A1-33-01B_압출+철콘+화장실; sets with these values: 2
Pset_WallCommon - LoadBearing: yes; ExtendToStructure: no; Reference: (복합)A2-22-02A+WA111(200_CW1)+A1-33-01B_압출+철콘+화장실

# IfcWall: 기본 벽:(복합)A2-22-02A+WA111(200_W1)+A1-32-06A_압출+철콘+수성 2, 기본 벽:(복합)A2-22-02A+WA111(200_W1)+A1-32-06A_압출+철콘+수성 2:6000353
In: 지상 10층
Type - PredefinedType: STANDARD; Material: WA240-ALC블록벽 35 mm, WA795-(STEEL)BRACKET 65 mm, WA821-압출스티로폼 벽 (본드붙임, 비중0.03) 50mm 50 mm, KBIMS-콘크리트 200 mm, WA555-콘크리트면정리 벽 (내부) 1 mm, WA551-시멘트모르타르 (내부) 벽 18mm 16 mm, WA611-수성페인트 (내부) 벽 (3회) 1 mm
Type - ID 데이터 - 단가: 0; 유형 마크: W1; 유형 이름: (복합)A2-22-02A+WA111(200_W1)+A1-32-06A_압출+철콘+수성 2
Type - 그래픽 - 거친 축척 채우기 색상: 0
Type - 기타 - 내화구조여부: yes; 주요구조부여부: yes; 카테고리: 벽; KBIMS-부위코드: E275; 조달청표준공사코드: AD+AFC100+AJM+AOD112322000+ANC132110000+AGA113100000+AGA441100000; 패밀리 이름: 기본 벽
Type - 시공 - 기능: 외부; 끝단부 마무리: 없음; 인서트 부위 마무리: 마무리하지 않음; 폭: 368 mm
Type - 재료 및 마감재 - 구조 재료: KBIMS-콘크리트
Type - 해석 특성 - 거칠기: 1; 열 저항(R): 2.067; 열 전달 계수(U): 0.483792 kg/K/s3; 열 질량: 333.256; 흡수율: 9290.3
Type - Pset_WallCommon - IsExternal: yes; ThermalTransmittance: 0.483792 kg/K/s3
ID 데이터 - 연관 있음: yes
공정 - 생성 공정: 새 구성
구속조건 - 베이스 간격띄우기: 0 mm; 매스와 관련됨: no; 룸 경계: yes; 베이스 확장 거리: 0 mm; 벽 베이스가 부착됩니다.: no; 상단 간격띄우기: 0 mm; 상단 확장 거리: 0 mm; 상단이 부착됩니다.: no; 위치선: 구조체 면:외부; 베이스 구속조건: 지상 10층; 상단 구속조건: 상위 레벨: 옥탑층; 미연결 높이: 5000 mm
구조 - 구조: yes; 보강 철근 피복 - 다른 면: 보강 철근 피복 1 <25 mm>; 구조적 용도: 교좌장치; 보강 철근 피복 - 내부 면: 보강 철근 피복 1 <25 mm>; 보강 철근 피복 - 외부 면: 보강 철근 피복 1 <25 mm>
기타 - 패밀리: 기본 벽; 유형: (복합)A2-22-02A+WA111(200_W1)+A1-32-06A_압출+철콘+수성 2; 유형 ID: 7718583; 패밀리 및 유형: 기본 벽: (복합)A2-22-02A+WA111(200_W1)+A1-32-06A_압출+철콘+수성 2
단면형상 정의 - 단면형상: 수직
치수 - 길이: 7034 mm; 면적: 31.85 m2; 체적: 11.6789 m3
Pset_QuantityTakeOff - Reference: (복합)A2-22-02A+WA111(200_W1)+A1-32-06A_압출+철콘+수성 2; sets with these values: 2
Pset_WallCommon - LoadBearing: yes; ExtendToStructure: no; Reference: (복합)A2-22-02A+WA111(200_W1)+A1-32-06A_압출+철콘+수성 2

# IfcWall: 기본 벽:(복합)WA111(200_CW1)+A1-32-06A_철콘+수성 (6)
In: 지상 10층
Type - PredefinedType: STANDARD; Material: WA611-수성페인트 (내부) 벽 (3회) 1 mm, WA551-시멘트모르타르 (내부) 벽 18mm 16 mm, WA555-콘크리트면정리 벽 (내부) 1 mm, KBIMS-콘크리트 200 mm, WA555-콘크리트면정리 벽 (내부) 1 mm, WA551-시멘트모르타르 (내부) 벽 18mm 16 mm, WA611-수성페인트 (내부) 벽 (3회) 1 mm
Type - ID 데이터 - 단가: 0; 유형 마크: CW1; 유형 이름: (복합)WA111(200_CW1)+A1-32-06A_철콘+수성
Type - 그래픽 - 거친 축척 채우기 색상: 0
Type - 기타 - 내화구조여부: yes; 주요구조부여부: yes; 카테고리: 벽; KBIMS-부위코드: E275; 조달청표준공사코드: AD+ANC132110000+AGA113100000+AGA441100000; 패밀리 이름: 기본 벽
Type - 시공 - 기능: 외부; 끝단부 마무리: 없음; 인서트 부위 마무리: 마무리하지 않음; 폭: 236 mm
Type - 재료 및 마감재 - 구조 재료: KBIMS-콘크리트
Type - 해석 특성 - 거칠기: 1; 열 저항(R): 0.239097; 열 전달 계수(U): 4.1824 kg/K/s3; 열 질량: 359.148; 흡수율: 9290.3
Type - Pset_WallCommon - IsExternal: yes; ThermalTransmittance: 4.1824 kg/K/s3
ID 데이터 - 연관 있음: yes
공정 - 생성 공정: 새 구성
구속조건 - 베이스 간격띄우기: 0 mm; 매스와 관련됨: no; 룸 경계: yes; 베이스 확장 거리: 0 mm; 벽 베이스가 부착됩니다.: no; 상단 간격띄우기: 0 mm; 상단 확장 거리: 0 mm; 상단이 부착됩니다.: no; 위치선: 구조체 면:외부; 베이스 구속조건: 지상 10층; 상단 구속조건: 상위 레벨: 옥탑층; 미연결 높이: 5000 mm
구조 - 구조: yes; 보강 철근 피복 - 다른 면: 보강 철근 피복 1 <25 mm>; 구조적 용도: 교좌장치; 보강 철근 피복 - 내부 면: 보강 철근 피복 1 <25 mm>; 보강 철근 피복 - 외부 면: 보강 철근 피복 1 <25 mm>
기타 - 패밀리: 기본 벽; 유형: (복합)WA111(200_CW1)+A1-32-06A_철콘+수성; 유형 ID: 7717580; 패밀리 및 유형: 기본 벽: (복합)WA111(200_CW1)+A1-32-06A_철콘+수성
단면형상 정의 - 단면형상: 수직
Pset_QuantityTakeOff - Reference: (복합)WA111(200_CW1)+A1-32-06A_철콘+수성; sets with these values: 2
Pset_WallCommon - LoadBearing: yes; ExtendToStructure: no; Reference: (복합)WA111(200_CW1)+A1-32-06A_철콘+수성
Name (기본 벽:(복합)WA111(200_CW1)+A1-32-06A_철콘+수성:...) | 길이 (mm) | 면적 (m2) | 체적 (m3)
2822389 | 12452.9 | 56.3488 | 13.285
2822391 | 5683.01 | 22.8049 | 5.3778
2822407 | 2323 | 7.28785 | 1.68081
2822411 | 6692.91 | 30.9022 | 7.18855
2822413 | 2817.99 | 10.3047 | 2.41833
2822415 | 6740 | 33.34 | 7.70711

# IfcWall: 기본 벽:(복합)WA111(200_CW1)+WA313_철콘+화강석잔다듬, 기본 벽:(복합)WA111(200_CW1)+WA313_철콘+화강석잔다듬:3178010
In: 지상 10층
Type - PredefinedType: STANDARD; Material: KBIMS_콘크리트 200 mm, KBIMS-화강석 잔다듬 80 mm
Type - ID 데이터 - 단가: 0; 유형 마크: CW1; 유형 이름: (복합)WA111(200_CW1)+WA313_철콘+화강석잔다듬
Type - 그래픽 - 거친 축척 채우기 색상: 0
Type - 기타 - 카테고리: 벽; KBIMS-부위코드: E24; 불연성재료: 불연재료; 조달청표준공사코드: AMB161A+AD; 패밀리 이름: 기본 벽
Type - 시공 - 기능: 외부; 끝단부 마무리: 없음; 인서트 부위 마무리: 마무리하지 않음; 폭: 280 mm
Type - 재료 및 마감재 - 구조 재료: KBIMS_콘크리트
Type - 해석 특성 - 거칠기: 1; 흡수율: 9290.3
Type - Pset_WallCommon - IsExternal: yes
공정 - 생성 공정: 새 구성
구속조건 - 베이스 간격띄우기: 0 mm; 매스와 관련됨: no; 룸 경계: yes; 베이스 확장 거리: 0 mm; 벽 베이스가 부착됩니다.: no; 상단 간격띄우기: 0 mm; 상단 확장 거리: 0 mm; 상단이 부착됩니다.: no; 베이스 구속조건: 지상 10층; 상단 구속조건: 상위 레벨: 옥탑층; 위치선: 마감면:외부; 미연결 높이: 5000 mm
구조 - 구조: no; 구조적 용도: 비교좌장치
기타 - 패밀리: 기본 벽; 유형: (복합)WA111(200_CW1)+WA313_철콘+화강석잔다듬; 유형 ID: 7719098; 패밀리 및 유형: 기본 벽: (복합)WA111(200_CW1)+WA313_철콘+화강석잔다듬
단면형상 정의 - 단면형상: 수직
치수 - 길이: 2464.99 mm; 면적: 13.025 m2; 체적: 3.57724 m3
Pset_QuantityTakeOff - Reference: (복합)WA111(200_CW1)+WA313_철콘+화강석잔다듬; sets with these values: 2
Pset_WallCommon - LoadBearing: no; ExtendToStructure: no; Reference: (복합)WA111(200_CW1)+WA313_철콘+화강석잔다듬

# IfcWall: 기본 벽:(복합)WA313+WA111(200_CW1)+A1-33-01B_화강석잔다듬+철콘+화장실, 기본 벽:(복합)WA313+WA111(200_CW1)+A1-33-01B_화강석잔다듬+철콘+화장실:2822393
In: 지상 10층
Type - PredefinedType: STANDARD; Material: KBIMS-화강석 잔다듬 80 mm, KBIMS_콘크리트 200 mm, WA551-시멘트모르타르 (내부) 벽 18mm 22 mm, WA352-도기질타일 벽 200x200 8 mm
Type - ID 데이터 - 단가: 0; 유형 마크: CW1; 유형 이름: (복합)WA313+WA111(200_CW1)+A1-33-01B_화강석잔다듬+철콘+화장실
Type - 그래픽 - 거친 축척 채우기 색상: 0
Type - 기타 - 카테고리: 벽; KBIMS-부위코드: E24; 불연성재료: 불연재료; 조달청표준공사코드: AMB161A+AD+AMB161A; 패밀리 이름: 기본 벽
Type - 시공 - 기능: 외부; 끝단부 마무리: 없음; 인서트 부위 마무리: 마무리하지 않음; 폭: 310 mm
Type - 재료 및 마감재 - 구조 재료: KBIMS_콘크리트
Type - 해석 특성 - 거칠기: 1; 열 저항(R): 0.0305556; 열 전달 계수(U): 32.7273 kg/K/s3; 열 질량: 33.396; 흡수율: 9290.3
Type - Pset_WallCommon - IsExternal: yes; ThermalTransmittance: 32.7273 kg/K/s3
ID 데이터 - 연관 있음: yes
공정 - 생성 공정: 새 구성
구속조건 - 베이스 간격띄우기: 0 mm; 매스와 관련됨: no; 룸 경계: yes; 베이스 확장 거리: 0 mm; 벽 베이스가 부착됩니다.: no; 상단 간격띄우기: 0 mm; 상단 확장 거리: 0 mm; 상단이 부착됩니다.: no; 베이스 구속조건: 지상 10층; 상단 구속조건: 상위 레벨: 옥탑층; 미연결 높이: 5000 mm; 위치선: 마감면:외부
구조 - 구조: yes; 보강 철근 피복 - 다른 면: 보강 철근 피복 1 <25 mm>; 구조적 용도: 교좌장치; 보강 철근 피복 - 내부 면: 보강 철근 피복 1 <25 mm>; 보강 철근 피복 - 외부 면: 보강 철근 피복 1 <25 mm>
기타 - 패밀리: 기본 벽; 유형: (복합)WA313+WA111(200_CW1)+A1-33-01B_화강석잔다듬+철콘+화장실; 유형 ID: 7720306; 패밀리 및 유형: 기본 벽: (복합)WA313+WA111(200_CW1)+A1-33-01B_화강석잔다듬+철콘+화장실
단면형상 정의 - 단면형상: 수직
치수 - 길이: 1359 mm; 면적: 5.6648 m2; 체적: 1.73927 m3
Pset_QuantityTakeOff - Reference: (복합)WA313+WA111(200_CW1)+A1-33-01B_화강석잔다듬+철콘+화장실; sets with these values: 2
Pset_WallCommon - LoadBearing: yes; ExtendToStructure: no; Reference: (복합)WA313+WA111(200_CW1)+A1-33-01B_화강석잔다듬+철콘+화장실

# IfcWall: 기본 벽:A1-32-06A-콘크리트면정리, 시멘트모르타르(미장용), 수성페인트(내부) (18mm) (38)
Type - PredefinedType: STANDARD; Material: WA611-수성페인트 (내부) 벽 (3회) 1 mm, WA551-시멘트모르타르 (내부) 벽 18mm 16 mm, WA555-콘크리트면정리 벽 (내부) 1 mm
Type - ID 데이터 - 단가: 0; 유형 이름: A1-32-06A-콘크리트면정리, 시멘트모르타르(미장용), 수성페인트(내부) (18mm)
Type - 그래픽 - 거친 축척 채우기 색상: 0
Type - 기타 - 카테고리: 벽; KBIMS-부위코드: E24; 불연성재료: 불연재료; 조달청표준공사코드: ANC132110000+AGA113100000+AGA441100000; 패밀리 이름: 기본 벽
Type - 시공 - 기능: 외부; 끝단부 마무리: 없음; 인서트 부위 마무리: 마무리하지 않음; 폭: 18 mm
Type - 해석 특성 - 거칠기: 1; 열 저항(R): 0.0239464; 열 전달 계수(U): 41.76 kg/K/s3; 열 질량: 28.4639; 흡수율: 30.48
Type - Pset_WallCommon - IsExternal: yes; ThermalTransmittance: 41.76 kg/K/s3
공정 - 생성 공정: 새 구성
구속조건 - 매스와 관련됨: no; 룸 경계: yes; 베이스 확장 거리: 0 mm; 벽 베이스가 부착됩니다.: no; 상단 확장 거리: 0 mm; 상단이 부착됩니다.: no; 위치선: 마감면:내부
구조 - 구조: no; 구조적 용도: 비교좌장치
기타 - 패밀리: 기본 벽; 유형: A1-32-06A-콘크리트면정리, 시멘트모르타르(미장용), 수성페인트(내부) (18mm); 유형 ID: 6825441; 패밀리 및 유형: 기본 벽: A1-32-06A-콘크리트면정리, 시멘트모르타르(미장용), 수성페인트(내부) (18mm)
단면형상 정의 - 단면형상: 수직
Pset_QuantityTakeOff - Reference: A1-32-06A-콘크리트면정리, 시멘트모르타르(미장용), 수성페인트(내부) (18mm); sets with these values: 2
Pset_WallCommon - LoadBearing: no; ExtendToStructure: no; Reference: A1-32-06A-콘크리트면정리, 시멘트모르타르(미장용), 수성페인트(내부) (18mm)
Name (기본 벽:A1-32-06A-콘크리트면정리, 시멘트모르타르(미장용), 수성페인트(내부) (18mm):...) | In | 상단 간격띄우기 (mm) | 베이스 구속조건 | 미연결 높이 (mm) | 베이스 간격띄우기 (mm) | 길이 (mm) | 면적 (m2) | 체적 (m3) | 상단 구속조건
7555800 | 지상 2층 | 0 | 지상 2층 | 3100 | 80 | 10328.5 | 23.5344 | 0.42362
7555813 | 지상 2층 | -1420 | 지상 2층 | 3000 | 80 | 17486 | 4.935 | 0.08883 | 상위 레벨: 지상 3층
7555814 | 지상 2층 | -1420 | 지상 2층 | 3000 | 80 | 16141 | 4.80005 | 0.0864009 | 상위 레벨: 지상 3층
7555816 | 지상 2층 | -1420 | 지상 2층 | 3000 | 80 | 5708.27 | 5.274 | 0.0690127 | 상위 레벨: 지상 3층
7555818 | 지상 2층 | -1420 | 지상 2층 | 3000 | 80 | 1591 | 1.95736 | 0.0352325 | 상위 레벨: 지상 3층
7557752 | 지상 3층 | 0 | 지상 3층 | 2900 | 80 | 7282 | 17.7084 | 0.318752
7557783 | 지상 3층 | 0 | 지상 3층 | 2900 | 80 | 2195 | 0.620285 | 0.0111651
7557800 | 지상 3층 | 0 | 지상 3층 | 2900 | 80 | 10550 | 22.838 | 0.411079
7561300 | 지상 4층 | 0 | 지상 4층 | 2835.27 | 80 | 10482 | 22.5104 | 0.405188
7562200 | 지상 5층 | 0 | 지상 5층 | 2900 | 80 | 10591 | 23.0618 | 0.415112
7563476 | 지상 6층 | 0 | 지상 6층 | 2900 | 80 | 2613.46 | 0.754048 | 0.0135729
7563498 | 지상 6층 | 0 | 지상 6층 | 2900 | 80 | 10482 | 23.0699 | 0.415257
7563560 | 지상 7층 | 0 | 지상 7층 | 2900 | 80 | 2622.4 | 0.806049 | 0.0145089
7563582 | 지상 7층 | 0 | 지상 7층 | 2900 | 80 | 10482 | 23.0699 | 0.415257
7563644 | 지상 8층 | 0 | 지상 8층 | 2900 | 80 | 2617.5 | 0.804953 | 0.0144892
7563666 | 지상 8층 | 0 | 지상 8층 | 2900 | 80 | 10482 | 23.0699 | 0.415258
7568170 | 지상 1층 | -1170 | 지상 1층 | 3550 | 80 | 7909.02 | 3.46884 | 0.0624391 | 상위 레벨: 지상 2층
7568193 | 지상 1층 | -1220 | 지상 1층 | 3500 | 80 | 13293.1 | 46.358 | 0.834445 | 상위 레벨: 지상 2층
7710097 | 지상 4층 | 0 | 지상 4층 | 3620 | 80 | 33582 | 47.7518 | 0.859533
7711462 | 지상 5층 | 0 | 지상 5층 | 4100 | 0 | 33582 | 59.2014 | 1.06563 | 상위 레벨: 지상 6층
7712230 | 지상 6층 | 0 | 지상 6층 | 4100 | 0 | 33582 | 59.2015 | 1.06563 | 상위 레벨: 지상 7층
7712310 | 지상 7층 | 0 | 지상 7층 | 4100 | 0 | 33582 | 59.2015 | 1.06563 | 상위 레벨: 지상 8층
7712385 | 지상 8층 | 0 | 지상 8층 | 4100 | 0 | 33782 | 59.5434 | 1.07178 | 상위 레벨: 지상 9층
7712460 | 지상 9층 | -400 | 지상 9층 | 4100 | 0 | 33782 | 56.5803 | 1.01845 | 상위 레벨: 지상 10층
7713597 | 지상 4층 | -400 | 지상 4층 | 3620 | 80 | 35782 | 35.764 | 0.643752 | 상위 레벨: 지상 5층
7714059 | 지상 5층 | -400 | 지상 5층 | 3620 | 80 | 35782 | 57.9377 | 1.04288 | 상위 레벨: 지상 6층
7714134 | 지상 6층 | -400 | 지상 6층 | 3620 | 80 | 35782 | 57.9377 | 1.04288 | 상위 레벨: 지상 7층
7714171 | 지상 7층 | -400 | 지상 7층 | 3620 | 80 | 35782 | 57.9377 | 1.04288 | 상위 레벨: 지상 8층
7714208 | 지상 8층 | -400 | 지상 8층 | 3620 | 80 | 35982 | 58.2785 | 1.04901 | 상위 레벨: 지상 9층
7714245 | 지상 9층 | -800 | 지상 9층 | 3620 | 80 | 35991 | 54.7108 | 0.984794 | 상위 레벨: 지상 10층
7715287 | 지상 4층 | -400 | 지상 4층 | 3620 | 80 | 27082 | 38.9774 | 0.701594 | 상위 레벨: 지상 5층
7715738 | 지상 5층 | -400 | 지상 5층 | 3620 | 80 | 27182 | 48.1428 | 0.866571 | 상위 레벨: 지상 6층
7715775 | 지상 6층 | -400 | 지상 6층 | 3620 | 80 | 27182 | 48.1428 | 0.86657 | 상위 레벨: 지상 7층
7715812 | 지상 7층 | -400 | 지상 7층 | 3620 | 80 | 27182 | 45.9697 | 0.827454 | 상위 레벨: 지상 8층
7716909 | 지상 8층 | -400 | 지상 8층 | 3620 | 80 | 27282 | 46.1497 | 0.830694 | 상위 레벨: 지상 9층
7716959 | 지상 9층 | -400 | 지상 9층 | 4020 | 80 | 27282 | 43.6372 | 0.785469 | 상위 레벨: 지상 10층
7740271 | 지상 1층 | -1170 | 지상 1층 | 4100 | -470 | 1482 | 3.21078 | 0.057794 | 상위 레벨: 지상 2층
7750515 | 지상 1층 | -1170 | 지상 1층 | 3550 | 80 | 7910 | 3.40497 | 0.0612894 | 상위 레벨: 지상 2층

# IfcWall: 기본 벽:A1-32-07A-콘크리트면정리, 바닥방수연장, 시멘트모르타르(미장용), 수성페인트(내부) (24mm) (10)
Type - PredefinedType: STANDARD; Material: WA611-수성페인트 (내부) 벽 (3회) 1 mm, WA551-시멘트모르타르 (내부) 벽 24mm 21 mm, WA961-바닥방수 연장 1 mm, WA555-콘크리트면정리 벽 (내부) 1 mm
Type - ID 데이터 - 단가: 0; 유형 이름: A1-32-07A-콘크리트면정리, 바닥방수연장, 시멘트모르타르(미장용), 수성페인트(내부) (24mm)
Type - 그래픽 - 거친 축척 채우기 색상: 0
Type - 기타 - 카테고리: 벽; KBIMS-부위코드: E24; 불연성재료: 불연재료; 조달청표준공사코드: ANC132110000+AGA114600000+AHG3+AGA441100000; 패밀리 이름: 기본 벽
Type - 시공 - 기능: 외부; 끝단부 마무리: 없음; 인서트 부위 마무리: 마무리하지 않음; 폭: 24 mm
Type - 해석 특성 - 거칠기: 1; 열 저항(R): 0.035006; 열 전달 계수(U): 28.5665 kg/K/s3; 열 질량: 37.8109; 흡수율: 30.48
Type - Pset_WallCommon - IsExternal: yes; ThermalTransmittance: 28.5665 kg/K/s3
공정 - 생성 공정: 새 구성
구속조건 - 매스와 관련됨: no; 룸 경계: yes; 베이스 확장 거리: 0 mm; 벽 베이스가 부착됩니다.: no; 상단 간격띄우기: 0 mm; 상단 확장 거리: 0 mm; 상단이 부착됩니다.: no; 위치선: 마감면:내부; 베이스 간격띄우기: 80 mm
구조 - 구조: no; 구조적 용도: 비교좌장치
기타 - 패밀리: 기본 벽; 유형: A1-32-07A-콘크리트면정리, 바닥방수연장, 시멘트모르타르(미장용), 수성페인트(내부) (24mm); 유형 ID: 6825625; 패밀리 및 유형: 기본 벽: A1-32-07A-콘크리트면정리, 바닥방수연장, 시멘트모르타르(미장용), 수성페인트(내부) (24mm)
단면형상 정의 - 단면형상: 수직
Pset_QuantityTakeOff - Reference: A1-32-07A-콘크리트면정리, 바닥방수연장, 시멘트모르타르(미장용), 수성페인트(내부) (24mm); sets with these values: 2
Pset_WallCommon - LoadBearing: no; ExtendToStructure: no; Reference: A1-32-07A-콘크리트면정리, 바닥방수연장, 시멘트모르타르(미장용), 수성페인트(내부) (24mm)
Name (기본 벽:A1-32-07A-콘크리트면정리, 바닥방수연장, 시멘트모르타르(미장용), 수성페인트(내부) (24mm):...) | In | 베이스 구속조건 | 미연결 높이 (mm) | 길이 (mm) | 면적 (m2) | 체적 (m3)
7557819 | 지상 3층 | 지상 3층 | 2600 | 17483 | 4.27691 | 0.102646
7557820 | 지상 3층 | 지상 3층 | 2600 | 16138 | 4.15992 | 0.099838
7557822 | 지상 3층 | 지상 3층 | 2600 | 5662.27 | 4.08308 | 0.0979939
7557824 | 지상 3층 | 지상 3층 | 2600 | 1587.74 | 1.36093 | 0.0326623
7561306 | 지상 4층 | 지상 4층 | 2600 | 1588 | 1.36108 | 0.0326659
7562712 | 지상 5층 | 지상 5층 | 2600 | 1588 | 1.36108 | 0.0326659
7563889 | 지상 6층 | 지상 6층 | 2600 | 1588 | 1.36108 | 0.0326659
7563902 | 지상 7층 | 지상 7층 | 2600 | 1588 | 1.36108 | 0.0326659
7563915 | 지상 8층 | 지상 8층 | 2600 | 1588 | 1.36108 | 0.0326659
7563928 | 지상 9층 | 지상 9층 | 2900 | 1588 | 1.80388 | 0.0432931

# IfcWall: 기본 벽:A2-22-02A-압출스티로폼, BRACKET(STEEL), ALC블록 (150mm), 기본 벽:A2-22-02A-압출스티로폼, BRACKET(STEEL), ALC블록 (150mm):2831748
In: 지상 1층
Type - PredefinedType: STANDARD; Material: WA240-ALC블록벽 35 mm, WA795-(STEEL)BRACKET 65 mm, WA821-압출스티로폼 벽 (본드붙임, 비중0.03) 50mm 50 mm
Type - ID 데이터 - 단가: 0; 유형 이름: A2-22-02A-압출스티로폼, BRACKET(STEEL), ALC블록 (150mm)
Type - 그래픽 - 거친 축척 채우기 색상: 0
Type - 기타 - 카테고리: 벽; KBIMS-부위코드: E24; 불연성재료: 불연재료; 조달청표준공사코드: AFC100+AJM+AOD112322000; 패밀리 이름: 기본 벽
Type - 시공 - 기능: 외부; 끝단부 마무리: 없음; 인서트 부위 마무리: 마무리하지 않음; 폭: 150 mm
Type - 해석 특성 - 거칠기: 1; 열 저항(R): 1.85185; 열 전달 계수(U): 0.54 kg/K/s3; 열 질량: 2.5725; 흡수율: 9290.3
Type - Pset_WallCommon - IsExternal: yes; ThermalTransmittance: 0.54 kg/K/s3
공정 - 생성 공정: 새 구성
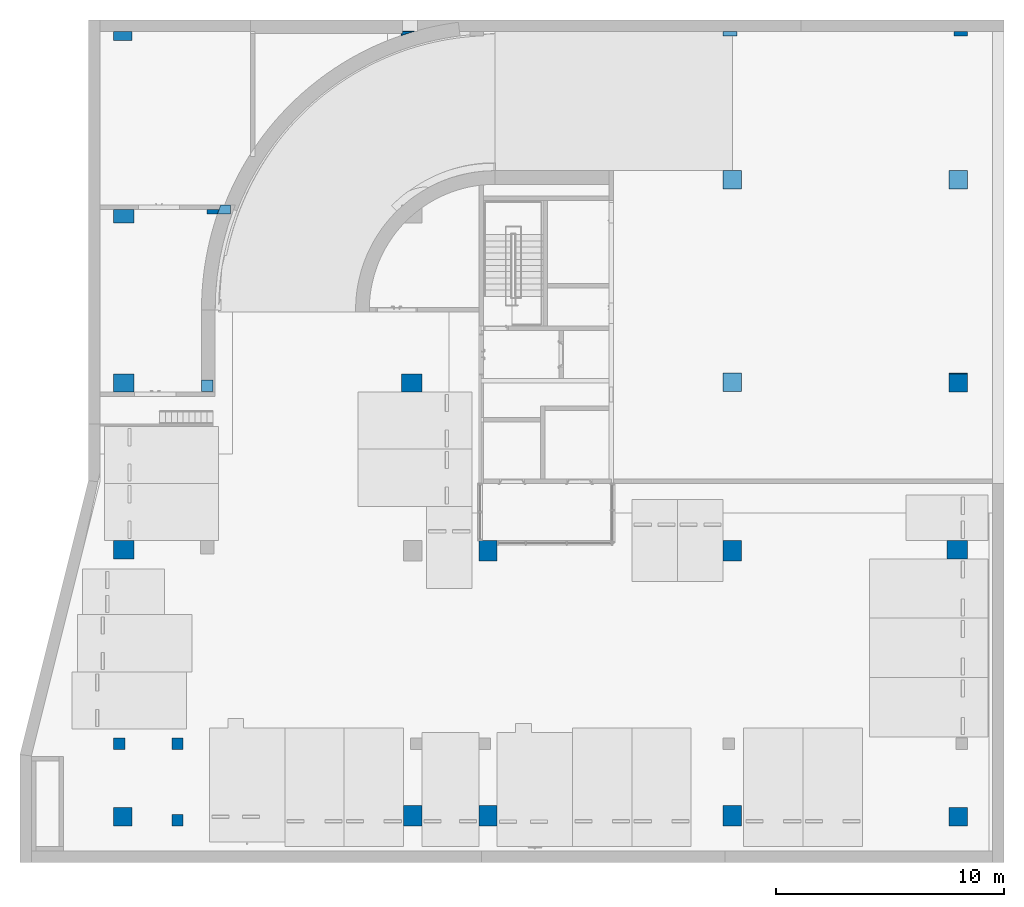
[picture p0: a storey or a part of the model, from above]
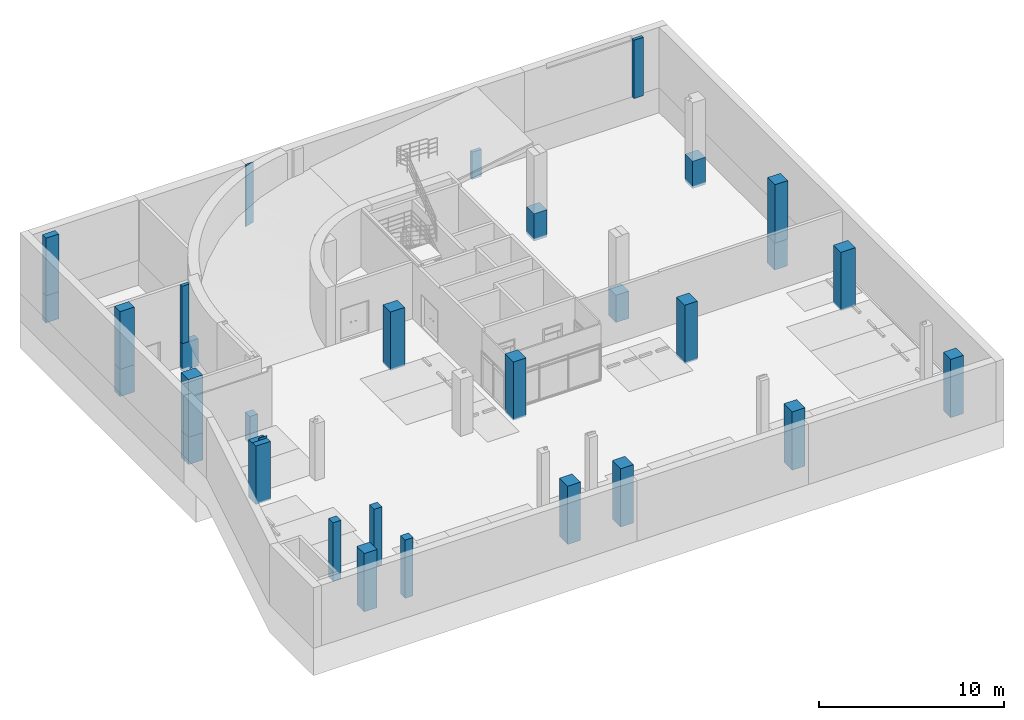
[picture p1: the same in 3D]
Properties of the parts of a building model (IFC2X3), part 34 of 39

# IfcWall: 기본 벽:A2-22-02A-압출스티로폼, BRACKET(STEEL), ALC블록 (150mm), 기본 벽:A2-22-02A-압출스티로폼, BRACKET(STEEL), ALC블록 (150mm):2831748
구속조건 - 매스와 관련됨: no; 룸 경계: yes; 베이스 확장 거리: 0 mm; 벽 베이스가 부착됩니다.: no; 상단 간격띄우기: 0 mm; 상단 확장 거리: 0 mm; 상단이 부착됩니다.: no; 베이스 구속조건: 지상 1층; 상단 구속조건: 상위 레벨: 지상 2층; 위치선: 마감면:외부; 미연결 높이: 5350 mm; 베이스 간격띄우기: -550 mm
구조 - 구조: no; 구조적 용도: 비교좌장치
기타 - 패밀리: 기본 벽; 유형: A2-22-02A-압출스티로폼, BRACKET(STEEL), ALC블록 (150mm); 유형 ID: 6831947; 패밀리 및 유형: 기본 벽: A2-22-02A-압출스티로폼, BRACKET(STEEL), ALC블록 (150mm)
단면형상 정의 - 단면형상: 수직
치수 - 길이: 7600 mm; 면적: 37.9783 m2; 체적: 5.69671 m3
Pset_QuantityTakeOff - Reference: A2-22-02A-압출스티로폼, BRACKET(STEEL), ALC블록 (150mm); sets with these values: 2
Pset_WallCommon - LoadBearing: no; ExtendToStructure: no; Reference: A2-22-02A-압출스티로폼, BRACKET(STEEL), ALC블록 (150mm)

# IfcWall: 기본 벽:WA111-철근콘크리트구조 벽 200mm_CW1 (47)
Type - PredefinedType: STANDARD; Material: KBIMS-콘크리트 200 mm
Type - ID 데이터 - 단가: 0; 유형 마크: CW1; 유형 이름: WA111-철근콘크리트구조 벽 200mm_CW1
Type - 그래픽 - 거친 축척 채우기 색상: 0
Type - 기타 - 내화구조여부: yes; 주요구조부여부: yes; 카테고리: 벽; KBIMS-부위코드: E275; 조달청표준공사코드: AD; 패밀리 이름: 기본 벽
Type - 시공 - 기능: 외부; 끝단부 마무리: 없음; 인서트 부위 마무리: 마무리하지 않음; 폭: 200 mm
Type - 재료 및 마감재 - 구조 재료: KBIMS-콘크리트
Type - 해석 특성 - 거칠기: 1; 열 저항(R): 0.191205; 열 전달 계수(U): 5.23 kg/K/s3; 열 질량: 302.22; 흡수율: 9290.3
Type - Pset_WallCommon - ThermalTransmittance: 5.23 kg/K/s3; IsExternal: yes
공정 - 생성 공정: 새 구성
구속조건 - 매스와 관련됨: no; 룸 경계: yes; 베이스 확장 거리: 0 mm; 벽 베이스가 부착됩니다.: no; 상단 확장 거리: 0 mm
기타 - 유형: WA111-철근콘크리트구조 벽 200mm_CW1; 유형 ID: 7430341; 패밀리: 기본 벽; 패밀리 및 유형: 기본 벽: WA111-철근콘크리트구조 벽 200mm_CW1
단면형상 정의 - 단면형상: 수직
Pset_QuantityTakeOff - Reference: WA111-철근콘크리트구조 벽 200mm_CW1; sets with these values: 2
Pset_WallCommon - Reference: WA111-철근콘크리트구조 벽 200mm_CW1
Name (기본 벽:WA111-철근콘크리트구조 벽 200mm_CW1:...) | In | 베이스 간격띄우기 (mm) | 미연결 높이 (mm) | 베이스 구속조건 | 상단 간격띄우기 (mm) | 상단 구속조건 | 상단이 부착됩니다. = ExtendToStructure | 위치선 | 구조 = LoadBearing | 구조적 용도 | 길이 (mm) | 면적 (m2) | 체적 (m3) | 연관 있음 | 보강 철근 피복 - 다른 면 | 보강 철근 피복 - 내부 면 | 보강 철근 피복 - 외부 면
2809108 | 지하2층 | 0 | 1800 | PIT | 0 | 상위 레벨: 지하2층 | yes | 벽 중심선 | no | 비교좌장치 | 9300 | 12.42 | 1.242
2809250 | 지하2층 | 0 | 1800 | PIT | 0 | 상위 레벨: 지하2층 | yes | 벽 중심선 | no | 비교좌장치 | 21250 | 17.448 | 3.4896
2813275 | 지하2층 | 0 | 4000 | 지하2층 | 0 | 상위 레벨: 지하1층 | no | 구조체 면:외부 | yes | 교좌장치 | 13268.7 | 48.1832 | 9.61063 | yes | 보강 철근 피복 1 <25 mm> | 보강 철근 피복 1 <25 mm> | 보강 철근 피복 1 <25 mm>
2813279 | 지하2층 | 0 | 4000 | 지하2층 | 0 | 상위 레벨: 지하1층 | no | 구조체 면:외부 | yes | 교좌장치 | 13600 | 52.072 | 10.4077 | yes | 보강 철근 피복 1 <25 mm> | 보강 철근 피복 1 <25 mm> | 보강 철근 피복 1 <25 mm>
2813523 | 지하2층 | 0 | 4000 | 지하2층 | 0 | 상위 레벨: 지하1층 | no | 구조체 면:외부 | yes | 교좌장치 | 5701.85 | 18.9821 | 3.79642 | yes | 보강 철근 피복 1 <25 mm> | 보강 철근 피복 1 <25 mm> | 보강 철근 피복 1 <25 mm>
2814040 | 지하2층 | 0 | 4000 | 지하2층 | 0 | 상위 레벨: 지하1층 | no | 구조체 면:외부 | yes | 교좌장치 | 2300 | 5.31055 | 1.06211 | yes | 보강 철근 피복 1 <25 mm> | 보강 철근 피복 1 <25 mm> | 보강 철근 피복 1 <25 mm>
2818037 | 지상 1층 | -600 | 5400 | 지상 1층 | 0 | 상위 레벨: 지상 2층 | no | 구조체 면:외부 | yes | 교좌장치 | 6201.84 | 30.1424 | 6.02847 | yes | 보강 철근 피복 1 <25 mm> | 보강 철근 피복 1 <25 mm> | 보강 철근 피복 1 <25 mm>
2818039 | 지상 1층 | 0 | 4800 | 지상 1층 | 0 | 상위 레벨: 지상 2층 | no | 구조체 면:외부 | yes | 교좌장치 | 12543.9 | 53.5202 | 10.608 | yes | 보강 철근 피복 1 <25 mm> | 보강 철근 피복 1 <25 mm> | 보강 철근 피복 1 <25 mm>
2818043 | 지상 1층 | -550 | 5350 | 지상 1층 | 0 | 상위 레벨: 지상 2층 | no | 구조체 면:외부 | yes | 교좌장치 | 5700 | 29.355 | 5.78551 | yes | 보강 철근 피복 1 <25 mm> | 보강 철근 피복 1 <25 mm> | 보강 철근 피복 1 <25 mm>
2818047 | 지상 1층 | -600 | 5400 | 지상 1층 | 0 | 상위 레벨: 지상 2층 | no | 구조체 면:외부 | yes | 교좌장치 | 6201.84 | 31.8096 | 6.36193 | yes | 보강 철근 피복 1 <25 mm> | 보강 철근 피복 1 <25 mm> | 보강 철근 피복 1 <25 mm>
2818057 | 지상 1층 | 0 | 4800 | 지상 1층 | 0 | 상위 레벨: 지상 2층 | no | 구조체 면:외부 | yes | 교좌장치 | 2300 | 6.96 | 1.37636 | yes | 보강 철근 피복 1 <25 mm> | 보강 철근 피복 1 <25 mm> | 보강 철근 피복 1 <25 mm>
2818914 | 지상 1층 | -500 | 5300 | 지상 1층 | 0 | 상위 레벨: 지상 2층 | no | 구조체 면:외부 | yes | 교좌장치 | 6700 | 36.2825 | 7.2565 | yes | 보강 철근 피복 1 <25 mm> | 보강 철근 피복 1 <25 mm> | 보강 철근 피복 1 <25 mm>
2819239 | 지상 1층 | -900 | 5700 | 지상 1층 | 0 | 상위 레벨: 지상 2층 | no | 구조체 면:외부 | yes | 교좌장치 | 2800 | 14.3 | 2.86 | yes | 보강 철근 피복 1 <25 mm> | 보강 철근 피복 1 <25 mm> | 보강 철근 피복 1 <25 mm>
2819318 | 지상 1층 | -1500 | 6300 | 지상 1층 | 0 | 상위 레벨: 지상 2층 | no | 구조체 면:외부 | yes | 교좌장치 | 6600 | 36.96 | 7.392 | yes | 보강 철근 피복 1 <25 mm> | 보강 철근 피복 1 <25 mm> | 보강 철근 피복 1 <25 mm>
2820032 | 지상 2층 | 0 | 4500 | 지상 2층 | 0 | 상위 레벨: 지상 3층 | no | 구조체 면:외부 | yes | 교좌장치 | 6200 | 26.4 | 5.28 | yes | 보강 철근 피복 1 <25 mm> | 보강 철근 피복 1 <25 mm> | 보강 철근 피복 1 <25 mm>
2820042 | 지상 2층 | 0 | 4500 | 지상 2층 | 0 | 상위 레벨: 지상 3층 | no | 구조체 면:외부 | yes | 교좌장치 | 2300 | 6.33 | 1.25036 | yes | 보강 철근 피복 1 <25 mm> | 보강 철근 피복 1 <25 mm> | 보강 철근 피복 1 <25 mm>
2820443 | 지상 3층 | 0 | 4100 | 지상 3층 | 0 | 상위 레벨: 지상 4층 | no | 구조체 면:외부 | yes | 교좌장치 | 12399.9 | 43.9906 | 8.79701 | yes | 보강 철근 피복 1 <25 mm> | 보강 철근 피복 1 <25 mm> | 보강 철근 피복 1 <25 mm>
2820445 | 지상 3층 | 0 | 4100 | 지상 3층 | 0 | 상위 레벨: 지상 4층 | no | 구조체 면:외부 | yes | 교좌장치 | 5700.01 | 16.6938 | 3.33877 | yes | 보강 철근 피복 1 <25 mm> | 보강 철근 피복 1 <25 mm> | 보강 철근 피복 1 <25 mm>
2820451 | 지상 3층 | 0 | 4100 | 지상 3층 | 0 | 상위 레벨: 지상 4층 | no | 구조체 면:외부 | yes | 교좌장치 | 6200 | 24 | 4.8 | yes | 보강 철근 피복 1 <25 mm> | 보강 철근 피복 1 <25 mm> | 보강 철근 피복 1 <25 mm>
2820461 | 지상 3층 | 0 | 4100 | 지상 3층 | 0 | 상위 레벨: 지상 4층 | no | 구조체 면:외부 | yes | 교좌장치 | 2300 | 5.49 | 1.08236 | yes | 보강 철근 피복 1 <25 mm> | 보강 철근 피복 1 <25 mm> | 보강 철근 피복 1 <25 mm>
2820465 | 지상 3층 | 0 | 4100 | 지상 3층 | 0 | 상위 레벨: 지상 4층 | no | 구조체 면:외부 | yes | 교좌장치 | 6699.91 | 24.6346 | 4.92281 | yes | 보강 철근 피복 1 <25 mm> | 보강 철근 피복 1 <25 mm> | 보강 철근 피복 1 <25 mm>
2820467 | 지상 3층 | 0 | 4100 | 지상 3층 | 0 | 상위 레벨: 지상 4층 | no | 구조체 면:외부 | yes | 교좌장치 | 2800 | 7.136 | 1.39583 | yes | 보강 철근 피복 1 <25 mm> | 보강 철근 피복 1 <25 mm> | 보강 철근 피복 1 <25 mm>
2820697 | 지상 4층 | 0 | 4100 | 지상 4층 | 0 | 상위 레벨: 지상 5층 | no | 구조체 면:외부 | yes | 교좌장치 | 5700 | 21.27 | 4.17151 | yes | 보강 철근 피복 1 <25 mm> | 보강 철근 피복 1 <25 mm> | 보강 철근 피복 1 <25 mm>
2820701 | 지상 4층 | 0 | 4100 | 지상 4층 | 0 | 상위 레벨: 지상 5층 | no | 구조체 면:외부 | yes | 교좌장치 | 6200 | 24 | 4.8 | yes | 보강 철근 피복 1 <25 mm> | 보강 철근 피복 1 <25 mm> | 보강 철근 피복 1 <25 mm>
2820711 | 지상 4층 | 0 | 4100 | 지상 4층 | 0 | 상위 레벨: 지상 5층 | no | 구조체 면:외부 | yes | 교좌장치 | 2300 | 5.49 | 1.08026 | yes | 보강 철근 피복 1 <25 mm> | 보강 철근 피복 1 <25 mm> | 보강 철근 피복 1 <25 mm>
2821195 | 지상 5층 | 0 | 4100 | 지상 5층 | 0 | 상위 레벨: 지상 6층 | no | 구조체 면:외부 | yes | 교좌장치 | 12403.9 | 44.1504 | 8.82746 | yes | 보강 철근 피복 1 <25 mm> | 보강 철근 피복 1 <25 mm> | 보강 철근 피복 1 <25 mm>
2821203 | 지상 5층 | 0 | 4100 | 지상 5층 | 0 | 상위 레벨: 지상 6층 | no | 구조체 면:외부 | yes | 교좌장치 | 6200 | 24 | 4.8 | yes | 보강 철근 피복 1 <25 mm> | 보강 철근 피복 1 <25 mm> | 보강 철근 피복 1 <25 mm>
2821213 | 지상 5층 | 0 | 4100 | 지상 5층 | 0 | 상위 레벨: 지상 6층 | no | 구조체 면:외부 | yes | 교좌장치 | 2300 | 5.49 | 1.08236 | yes | 보강 철근 피복 1 <25 mm> | 보강 철근 피복 1 <25 mm> | 보강 철근 피복 1 <25 mm>
2821455 | 지상 6층 | 0 | 4100 | 지상 6층 | 0 | 상위 레벨: 지상 7층 | no | 구조체 면:외부 | yes | 교좌장치 | 12403.9 | 44.0064 | 8.79022 | yes | 보강 철근 피복 1 <25 mm> | 보강 철근 피복 1 <25 mm> | 보강 철근 피복 1 <25 mm>
2821459 | 지상 6층 | 0 | 4100 | 지상 6층 | 0 | 상위 레벨: 지상 7층 | no | 구조체 면:외부 | yes | 교좌장치 | 5700 | 21.168 | 4.15111 | yes | 보강 철근 피복 1 <25 mm> | 보강 철근 피복 1 <25 mm> | 보강 철근 피복 1 <25 mm>
2821463 | 지상 6층 | 0 | 4100 | 지상 6층 | 0 | 상위 레벨: 지상 7층 | no | 구조체 면:외부 | yes | 교좌장치 | 6200 | 24 | 4.8 | yes | 보강 철근 피복 1 <25 mm> | 보강 철근 피복 1 <25 mm> | 보강 철근 피복 1 <25 mm>
2821473 | 지상 6층 | 0 | 4100 | 지상 6층 | 0 | 상위 레벨: 지상 7층 | no | 구조체 면:외부 | yes | 교좌장치 | 2300 | 5.49 | 1.08236 | yes | 보강 철근 피복 1 <25 mm> | 보강 철근 피복 1 <25 mm> | 보강 철근 피복 1 <25 mm>
2821659 | 지상 7층 | 0 | 4100 | 지상 7층 | 0 | 상위 레벨: 지상 8층 | no | 구조체 면:외부 | yes | 교좌장치 | 6200 | 24 | 4.8 | yes | 보강 철근 피복 1 <25 mm> | 보강 철근 피복 1 <25 mm> | 보강 철근 피복 1 <25 mm>
2821669 | 지상 7층 | 0 | 4100 | 지상 7층 | 0 | 상위 레벨: 지상 8층 | no | 구조체 면:외부 | yes | 교좌장치 | 2300 | 5.49 | 1.08236 | yes | 보강 철근 피복 1 <25 mm> | 보강 철근 피복 1 <25 mm> | 보강 철근 피복 1 <25 mm>
2821997 | 지상 8층 | 0 | 4100 | 지상 8층 | 0 | 상위 레벨: 지상 9층 | no | 구조체 면:외부 | yes | 교좌장치 | 12403.9 | 44.1504 | 8.81886 | yes | 보강 철근 피복 1 <25 mm> | 보강 철근 피복 1 <25 mm> | 보강 철근 피복 1 <25 mm>
2822005 | 지상 8층 | 0 | 4100 | 지상 8층 | 0 | 상위 레벨: 지상 9층 | no | 구조체 면:외부 | yes | 교좌장치 | 6200 | 24 | 4.8 | yes |  | 보강 철근 피복 1 <25 mm> | 보강 철근 피복 1 <25 mm>
2822015 | 지상 8층 | 0 | 4100 | 지상 8층 | 0 | 상위 레벨: 지상 9층 | no | 구조체 면:외부 | yes | 교좌장치 | 2300 | 5.49 | 1.08236 | yes | 보강 철근 피복 1 <25 mm> | 보강 철근 피복 1 <25 mm> | 보강 철근 피복 1 <25 mm>
2822207 | 지상 9층 | 0 | 4500 | 지상 9층 | 0 | 상위 레벨: 지상 10층 | no | 구조체 면:외부 | yes | 교좌장치 | 5700 | 23.55 | 4.62751 | yes | 보강 철근 피복 1 <25 mm> | 보강 철근 피복 1 <25 mm> | 보강 철근 피복 1 <25 mm>
2822211 | 지상 9층 | 0 | 4500 | 지상 9층 | 0 | 상위 레벨: 지상 10층 | no | 구조체 면:외부 | yes | 교좌장치 | 6200 | 26.4 | 5.28 | yes | 보강 철근 피복 1 <25 mm> | 보강 철근 피복 1 <25 mm> | 보강 철근 피복 1 <25 mm>
2822221 | 지상 9층 | 0 | 4500 | 지상 9층 | 0 | 상위 레벨: 지상 10층 | no | 구조체 면:외부 | yes | 교좌장치 | 2300 | 6.33 | 1.25036 | yes | 보강 철근 피복 1 <25 mm> | 보강 철근 피복 1 <25 mm> | 보강 철근 피복 1 <25 mm>
2822815 | 옥탑층 | 0 | 4700 | 옥탑층 | 700 | 상위 레벨: 지붕층 | yes | 구조체 면:외부 | yes | 교좌장치 | 10701.8 | 32.6221 | 6.39681 | yes | 보강 철근 피복 1 <25 mm> | 보강 철근 피복 1 <25 mm>
3150566 | 지하2층 | 0 | 1800 | PIT | 0 | 상위 레벨: 지하2층 | no | 구조체 면:외부 | yes | 교좌장치 | 22751.8 | 37.3073 | 7.46146 | yes | 보강 철근 피복 1 <25 mm> | 보강 철근 피복 1 <25 mm> | 보강 철근 피복 1 <25 mm>
3184373 | 지상 1층 | -550 | 900 | 지상 1층 | 350 | 상위 레벨: 지상 1층 | no | 구조체 면:외부 | yes | 교좌장치 | 725 | 0.71625 | 0.14325 | yes | 보강 철근 피복 1 <25 mm> | 보강 철근 피복 1 <25 mm> | 보강 철근 피복 1 <25 mm>
5329805 | 지하2층 | 0 | 1800 | PIT | 0 | 상위 레벨: 지하2층 | no | 구조체 면:외부 | yes | 교좌장치 | 5731.18 | 9.05721 | 1.80664 | yes | 보강 철근 피복 1 <25 mm> | 보강 철근 피복 1 <25 mm> | 보강 철근 피복 1 <25 mm>
5342341 | 지상 1층 | -550 | 5350 | 지상 1층 | 0 | 상위 레벨: 지상 2층 | no | 구조체 면:외부 | yes | 교좌장치 | 7460 | 36.6711 | 7.33414 | yes | 보강 철근 피복 1 <25 mm> | 보강 철근 피복 1 <25 mm> | 보강 철근 피복 1 <25 mm>
5461682 | 지상 1층 | -500 | 5300 | 지상 1층 | 0 | 상위 레벨: 지상 2층 | no | 구조체 면:외부 | yes | 교좌장치 | 9000 | 13.32 | 2.592 | yes | 보강 철근 피복 1 <25 mm> | 보강 철근 피복 1 <25 mm> | 보강 철근 피복 1 <25 mm>
5865847 | 지하1층 | 0 | 6100 | 지하1층 | 0 | 상위 레벨: 지상 1층 | no | 구조체 면:외부 | yes | 교좌장치 | 6703.91 | 40.2338 | 8.04677 | yes | 보강 철근 피복 1 <25 mm> | 보강 철근 피복 1 <25 mm> | 보강 철근 피복 1 <25 mm>

# IfcWall: 기본 벽:WA111-철근콘크리트구조 벽 200mm_CW3 (2)
In: 지하1층
Type - PredefinedType: STANDARD; Material: KBIMS-콘크리트 200 mm
Type - ID 데이터 - 단가: 0; 유형 마크: CW3; 유형 이름: WA111-철근콘크리트구조 벽 200mm_CW3
Type - 그래픽 - 거친 축척 채우기 색상: 0
Type - 기타 - 내화구조여부: yes; 주요구조부여부: yes; 카테고리: 벽; KBIMS-부위코드: E275; 조달청표준공사코드: AD; 패밀리 이름: 기본 벽
Type - 시공 - 기능: 외부; 끝단부 마무리: 없음; 인서트 부위 마무리: 마무리하지 않음; 폭: 200 mm
Type - 재료 및 마감재 - 구조 재료: KBIMS-콘크리트
Type - 해석 특성 - 거칠기: 1; 열 저항(R): 0.191205; 열 전달 계수(U): 5.23 kg/K/s3; 열 질량: 302.22; 흡수율: 9290.3
Type - Pset_WallCommon - IsExternal: yes; ThermalTransmittance: 5.23 kg/K/s3
ID 데이터 - 연관 있음: yes
공정 - 생성 공정: 새 구성
구속조건 - 베이스 간격띄우기: 0 mm; 매스와 관련됨: no; 룸 경계: yes; 베이스 확장 거리: 0 mm; 벽 베이스가 부착됩니다.: no; 상단 간격띄우기: 0 mm; 상단 확장 거리: 0 mm; 상단이 부착됩니다.: no; 위치선: 구조체 면:외부; 베이스 구속조건: 지하1층; 상단 구속조건: 상위 레벨: 지상 1층; 미연결 높이: 6100 mm
구조 - 구조: yes; 보강 철근 피복 - 다른 면: 보강 철근 피복 1 <25 mm>; 구조적 용도: 교좌장치; 보강 철근 피복 - 내부 면: 보강 철근 피복 1 <25 mm>; 보강 철근 피복 - 외부 면: 보강 철근 피복 1 <25 mm>
기타 - 패밀리: 기본 벽; 유형: WA111-철근콘크리트구조 벽 200mm_CW3; 유형 ID: 7626044; 패밀리 및 유형: 기본 벽: WA111-철근콘크리트구조 벽 200mm_CW3
단면형상 정의 - 단면형상: 수직
Pset_QuantityTakeOff - Reference: WA111-철근콘크리트구조 벽 200mm_CW3; sets with these values: 2
Pset_WallCommon - LoadBearing: yes; ExtendToStructure: no; Reference: WA111-철근콘크리트구조 벽 200mm_CW3
Name (기본 벽:WA111-철근콘크리트구조 벽 200mm_CW3:...) | 길이 (mm) | 면적 (m2) | 체적 (m3)
2816465 | 5701.85 | 28.7002 | 5.7336
2816481 | 2300 | 9.96723 | 1.97456

# IfcWall: 기본 벽:WA111-철근콘크리트구조 벽 200mm_W1 (3)
Type - PredefinedType: STANDARD; Material: KBIMS-콘크리트 200 mm
Type - ID 데이터 - 단가: 0; 유형 마크: W1; 유형 이름: WA111-철근콘크리트구조 벽 200mm_W1
Type - 그래픽 - 거친 축척 채우기 색상: 0
Type - 기타 - 내화구조여부: yes; 주요구조부여부: yes; 카테고리: 벽; KBIMS-부위코드: E275; 조달청표준공사코드: AD; 패밀리 이름: 기본 벽
Type - 시공 - 기능: 외부; 끝단부 마무리: 없음; 인서트 부위 마무리: 마무리하지 않음; 폭: 200 mm
Type - 재료 및 마감재 - 구조 재료: KBIMS-콘크리트
Type - 해석 특성 - 거칠기: 1; 열 저항(R): 0.191205; 열 전달 계수(U): 5.23 kg/K/s3; 열 질량: 302.22; 흡수율: 9290.3
Type - Pset_WallCommon - IsExternal: yes; ThermalTransmittance: 5.23 kg/K/s3
ID 데이터 - 연관 있음: yes
공정 - 생성 공정: 새 구성
구속조건 - 베이스 간격띄우기: 0 mm; 매스와 관련됨: no; 룸 경계: yes; 베이스 확장 거리: 0 mm; 벽 베이스가 부착됩니다.: no; 상단 확장 거리: 0 mm; 상단이 부착됩니다.: no; 위치선: 구조체 면:외부
구조 - 구조: yes; 보강 철근 피복 - 다른 면: 보강 철근 피복 1 <25 mm>; 구조적 용도: 교좌장치; 보강 철근 피복 - 내부 면: 보강 철근 피복 1 <25 mm>; 보강 철근 피복 - 외부 면: 보강 철근 피복 1 <25 mm>
기타 - 패밀리: 기본 벽; 유형: WA111-철근콘크리트구조 벽 200mm_W1; 유형 ID: 7626970; 패밀리 및 유형: 기본 벽: WA111-철근콘크리트구조 벽 200mm_W1
단면형상 정의 - 단면형상: 수직
Pset_QuantityTakeOff - Reference: WA111-철근콘크리트구조 벽 200mm_W1; sets with these values: 2
Pset_WallCommon - LoadBearing: yes; ExtendToStructure: no; Reference: WA111-철근콘크리트구조 벽 200mm_W1
Name (기본 벽:WA111-철근콘크리트구조 벽 200mm_W1:...) | In | 상단 간격띄우기 (mm) | 베이스 구속조건 | 상단 구속조건 | 미연결 높이 (mm) | 길이 (mm) | 면적 (m2) | 체적 (m3)
2813277 | 지하2층 | 0 | 지하2층 | 상위 레벨: 지하1층 | 4000 | 16950 | 64.05 | 12.81
2816491 | 지하1층 | -150 | 지하1층 | 상위 레벨: 지상 1층 | 5950 | 6811.28 | 33.2729 | 6.58754
2816493 | 지하1층 | -150 | 지하1층 | 상위 레벨: 지상 1층 | 5950 | 5149.99 | 29.86 | 5.97199

# IfcWall: 기본 벽:WA111-철근콘크리트구조 벽 300mm_RaW1 (2)
Type - PredefinedType: STANDARD; Material: KBIMS-콘크리트 600 mm
Type - ID 데이터 - 단가: 0; 유형 마크: RaW1; 유형 이름: WA111-철근콘크리트구조 벽 300mm_RaW1
Type - 그래픽 - 거친 축척 채우기 색상: 0
Type - 기타 - 내화구조여부: yes; 주요구조부여부: yes; 카테고리: 벽; KBIMS-부위코드: E275; 조달청표준공사코드: AD; 패밀리 이름: 기본 벽
Type - 시공 - 기능: 외부; 끝단부 마무리: 없음; 인서트 부위 마무리: 마무리하지 않음; 폭: 600 mm
Type - 재료 및 마감재 - 구조 재료: KBIMS-콘크리트
Type - 해석 특성 - 거칠기: 1; 열 저항(R): 0.573614; 열 전달 계수(U): 1.74333 kg/K/s3; 열 질량: 906.66; 흡수율: 9290.3
Type - Pset_WallCommon - IsExternal: yes; ThermalTransmittance: 1.74333 kg/K/s3
공정 - 생성 공정: 새 구성
구속조건 - 베이스 간격띄우기: 0 mm; 매스와 관련됨: no; 룸 경계: yes; 베이스 확장 거리: 0 mm; 벽 베이스가 부착됩니다.: no; 상단 확장 거리: 0 mm; 상단이 부착됩니다.: no
기타 - 패밀리: 기본 벽; 유형: WA111-철근콘크리트구조 벽 300mm_RaW1; 유형 ID: 7627184; 패밀리 및 유형: 기본 벽: WA111-철근콘크리트구조 벽 300mm_RaW1
단면형상 정의 - 단면형상: 수직
Pset_QuantityTakeOff - Reference: WA111-철근콘크리트구조 벽 300mm_RaW1; sets with these values: 2
Pset_WallCommon - ExtendToStructure: no; Reference: WA111-철근콘크리트구조 벽 300mm_RaW1
Name (기본 벽:WA111-철근콘크리트구조 벽 300mm_RaW1:...) | In | 위치선 | 베이스 구속조건 | 상단 구속조건 | 미연결 높이 (mm) | 상단 간격띄우기 (mm) | 구조 = LoadBearing | 구조적 용도 | 길이 (mm) | 면적 (m2) | 체적 (m3)
2816487 | 지하1층 | 구조체 면:외부 | 지하1층 | 상위 레벨: 지상 1층 | 5950 | -150 | yes | 교좌장치 | 9110.62 | 57.467 | 32.8538 | ID 데이터 - 연관 있음: yes; 구조 - 보강 철근 피복 - 다른 면: 보강 철근 피복 1 <25 mm>; 보강 철근 피복 - 내부 면: 보강 철근 피복 1 <25 mm>; 보강 철근 피복 - 외부 면: 보강 철근 피복 1 <25 mm>; 그래픽 - 중심 마크 보기: no
5345098 | 지하2층 | 벽 중심선 | 지하2층 | 상위 레벨: 지하1층 | 4000 | 0 | no | 비교좌장치 | 3700 | 14.4 | 8.45626

# IfcWall: 기본 벽:WA111-철근콘크리트구조 벽 500mm_BW1 (3)
In: 지하1층
Type - PredefinedType: STANDARD; Material: KBIMS-콘크리트 500 mm
Type - ID 데이터 - 단가: 0; 유형 마크: BW1; 유형 이름: WA111-철근콘크리트구조 벽 500mm_BW1
Type - 그래픽 - 거친 축척 채우기 색상: 0
Type - 기타 - 내화구조여부: yes; 주요구조부여부: yes; 카테고리: 벽; KBIMS-부위코드: E275; 조달청표준공사코드: AD; 패밀리 이름: 기본 벽
Type - 시공 - 기능: 외부; 끝단부 마무리: 없음; 인서트 부위 마무리: 마무리하지 않음; 폭: 500 mm
Type - 재료 및 마감재 - 구조 재료: KBIMS-콘크리트
Type - 해석 특성 - 거칠기: 1; 열 저항(R): 0.478011; 열 전달 계수(U): 2.092 kg/K/s3; 열 질량: 755.55; 흡수율: 9290.3
Type - Pset_WallCommon - IsExternal: yes; ThermalTransmittance: 2.092 kg/K/s3
ID 데이터 - 연관 있음: yes
공정 - 생성 공정: 새 구성
구속조건 - 베이스 간격띄우기: 0 mm; 매스와 관련됨: no; 룸 경계: yes; 베이스 확장 거리: 0 mm; 벽 베이스가 부착됩니다.: no; 상단 간격띄우기: 0 mm; 상단 확장 거리: 0 mm; 상단이 부착됩니다.: no; 위치선: 구조체 면:외부; 미연결 높이: 6100 mm; 베이스 구속조건: 지하1층; 상단 구속조건: 상위 레벨: 지상 1층
구조 - 구조: yes; 보강 철근 피복 - 다른 면: 보강 철근 피복 1 <25 mm>; 구조적 용도: 교좌장치; 보강 철근 피복 - 내부 면: 보강 철근 피복 1 <25 mm>; 보강 철근 피복 - 외부 면: 보강 철근 피복 1 <25 mm>
기타 - 패밀리: 기본 벽; 유형: WA111-철근콘크리트구조 벽 500mm_BW1; 유형 ID: 7626851; 패밀리 및 유형: 기본 벽: WA111-철근콘크리트구조 벽 500mm_BW1
단면형상 정의 - 단면형상: 수직
Pset_QuantityTakeOff - Reference: WA111-철근콘크리트구조 벽 500mm_BW1; sets with these values: 2
Pset_WallCommon - LoadBearing: yes; Reference: WA111-철근콘크리트구조 벽 500mm_BW1; ExtendToStructure: no
Name (기본 벽:WA111-철근콘크리트구조 벽 500mm_BW1:...) | 길이 (mm) | 면적 (m2) | 체적 (m3)
2815695 | 4443.84 | 28.8202 | 13.9492
2815699 | 6506.16 | 39.3053 | 19.5588
3111500 | 12369.3 | 75.4528 | 37.0162

# IfcWall: 기본 벽:WA111-철근콘크리트구조 벽 500mm_BW3 (2)
Type - PredefinedType: STANDARD; Material: KBIMS-콘크리트 500 mm
Type - ID 데이터 - 단가: 0; 유형 마크: BW3; 유형 이름: WA111-철근콘크리트구조 벽 500mm_BW3
Type - 그래픽 - 거친 축척 채우기 색상: 0
Type - 기타 - 내화구조여부: yes; 주요구조부여부: yes; 카테고리: 벽; KBIMS-부위코드: E275; 조달청표준공사코드: AD; 패밀리 이름: 기본 벽
Type - 시공 - 기능: 외부; 끝단부 마무리: 없음; 인서트 부위 마무리: 마무리하지 않음; 폭: 500 mm
Type - 재료 및 마감재 - 구조 재료: KBIMS-콘크리트
Type - 해석 특성 - 거칠기: 1; 열 저항(R): 0.478011; 열 전달 계수(U): 2.092 kg/K/s3; 열 질량: 755.55; 흡수율: 9290.3
Type - Pset_WallCommon - IsExternal: yes; ThermalTransmittance: 2.092 kg/K/s3
ID 데이터 - 연관 있음: yes
공정 - 생성 공정: 새 구성
구속조건 - 베이스 간격띄우기: 0 mm; 매스와 관련됨: no; 룸 경계: yes; 베이스 확장 거리: 0 mm; 벽 베이스가 부착됩니다.: no; 상단 간격띄우기: 0 mm; 상단 확장 거리: 0 mm; 상단이 부착됩니다.: no; 위치선: 구조체 면:외부
구조 - 구조: yes; 보강 철근 피복 - 다른 면: 보강 철근 피복 1 <25 mm>; 구조적 용도: 교좌장치; 보강 철근 피복 - 내부 면: 보강 철근 피복 1 <25 mm>; 보강 철근 피복 - 외부 면: 보강 철근 피복 1 <25 mm>
기타 - 패밀리: 기본 벽; 유형: WA111-철근콘크리트구조 벽 500mm_BW3; 유형 ID: 7626733; 패밀리 및 유형: 기본 벽: WA111-철근콘크리트구조 벽 500mm_BW3
단면형상 정의 - 단면형상: 수직
Pset_QuantityTakeOff - Reference: WA111-철근콘크리트구조 벽 500mm_BW3; sets with these values: 2
Pset_WallCommon - LoadBearing: yes; ExtendToStructure: no; Reference: WA111-철근콘크리트구조 벽 500mm_BW3
Name (기본 벽:WA111-철근콘크리트구조 벽 500mm_BW3:...) | In | 베이스 구속조건 | 상단 구속조건 | 미연결 높이 (mm) | 길이 (mm) | 면적 (m2) | 체적 (m3)
2815703 | 지하1층 | 지하1층 | 상위 레벨: 지상 1층 | 6100 | 36400 | 182.747 | 91.3733
5329921 | 지하2층 | 지하2층 | 상위 레벨: 지하1층 | 4000 | 8650 | 35.6 | 17.6404

# IfcWall: 기본 벽:WA111-철근콘크리트구조 벽 500mm_BW4 (2)
Type - PredefinedType: STANDARD; Material: KBIMS-콘크리트 500 mm
Type - ID 데이터 - 단가: 0; 유형 마크: BW4; 유형 이름: WA111-철근콘크리트구조 벽 500mm_BW4
Type - 그래픽 - 거친 축척 채우기 색상: 0
Type - 기타 - 내화구조여부: yes; 주요구조부여부: yes; 카테고리: 벽; KBIMS-부위코드: E275; 조달청표준공사코드: AD; 패밀리 이름: 기본 벽
Type - 시공 - 기능: 외부; 끝단부 마무리: 없음; 인서트 부위 마무리: 마무리하지 않음; 폭: 500 mm
Type - 재료 및 마감재 - 구조 재료: KBIMS-콘크리트
Type - 해석 특성 - 거칠기: 1; 열 저항(R): 0.478011; 열 전달 계수(U): 2.092 kg/K/s3; 열 질량: 755.55; 흡수율: 9290.3
Type - Pset_WallCommon - IsExternal: yes; ThermalTransmittance: 2.092 kg/K/s3
ID 데이터 - 연관 있음: yes
공정 - 생성 공정: 새 구성
구속조건 - 베이스 간격띄우기: 0 mm; 매스와 관련됨: no; 룸 경계: yes; 베이스 확장 거리: 0 mm; 벽 베이스가 부착됩니다.: no; 상단 간격띄우기: 0 mm; 상단 확장 거리: 0 mm; 상단이 부착됩니다.: no; 위치선: 구조체 면:외부; 베이스 구속조건: 지하1층; 상단 구속조건: 상위 레벨: 지상 1층; 미연결 높이: 6100 mm
구조 - 구조: yes; 보강 철근 피복 - 다른 면: 보강 철근 피복 1 <25 mm>; 구조적 용도: 교좌장치; 보강 철근 피복 - 내부 면: 보강 철근 피복 1 <25 mm>; 보강 철근 피복 - 외부 면: 보강 철근 피복 1 <25 mm>
기타 - 패밀리: 기본 벽; 유형: WA111-철근콘크리트구조 벽 500mm_BW4; 유형 ID: 7626681; 패밀리 및 유형: 기본 벽: WA111-철근콘크리트구조 벽 500mm_BW4
단면형상 정의 - 단면형상: 수직
치수 - 길이: 17500 mm; 면적: 103.25 m2; 체적: 50.9779 m3
Pset_QuantityTakeOff - Reference: WA111-철근콘크리트구조 벽 500mm_BW4; sets with these values: 2
Pset_WallCommon - LoadBearing: yes; ExtendToStructure: no; Reference: WA111-철근콘크리트구조 벽 500mm_BW4
Name (기본 벽:WA111-철근콘크리트구조 벽 500mm_BW4:...) | In
5338020 | 지하1층
5338020 | 지상 1층

# IfcWall: 기본 벽:WA111-철근콘크리트구조 벽 500mm_BW5 (3)
In: 지하1층
Type - PredefinedType: STANDARD; Material: KBIMS-콘크리트 500 mm
Type - ID 데이터 - 단가: 0; 유형 마크: BW5; 유형 이름: WA111-철근콘크리트구조 벽 500mm_BW5
Type - 그래픽 - 거친 축척 채우기 색상: 0
Type - 기타 - 내화구조여부: yes; 주요구조부여부: yes; 카테고리: 벽; KBIMS-부위코드: E275; 조달청표준공사코드: AD; 패밀리 이름: 기본 벽
Type - 시공 - 기능: 외부; 끝단부 마무리: 없음; 인서트 부위 마무리: 마무리하지 않음; 폭: 500 mm
Type - 재료 및 마감재 - 구조 재료: KBIMS-콘크리트
Type - 해석 특성 - 거칠기: 1; 열 저항(R): 0.478011; 열 전달 계수(U): 2.092 kg/K/s3; 열 질량: 755.55; 흡수율: 9290.3
Type - Pset_WallCommon - IsExternal: yes; ThermalTransmittance: 2.092 kg/K/s3
ID 데이터 - 연관 있음: yes
공정 - 생성 공정: 새 구성
구속조건 - 베이스 간격띄우기: 0 mm; 매스와 관련됨: no; 룸 경계: yes; 베이스 확장 거리: 0 mm; 벽 베이스가 부착됩니다.: no; 상단 간격띄우기: 0 mm; 상단 확장 거리: 0 mm; 상단이 부착됩니다.: no; 위치선: 구조체 면:외부; 베이스 구속조건: 지하1층; 상단 구속조건: 상위 레벨: 지상 1층; 미연결 높이: 6100 mm
구조 - 구조: yes; 보강 철근 피복 - 다른 면: 보강 철근 피복 1 <25 mm>; 구조적 용도: 교좌장치; 보강 철근 피복 - 내부 면: 보강 철근 피복 1 <25 mm>; 보강 철근 피복 - 외부 면: 보강 철근 피복 1 <25 mm>
기타 - 패밀리: 기본 벽; 유형: WA111-철근콘크리트구조 벽 500mm_BW5; 유형 ID: 7626577; 패밀리 및 유형: 기본 벽: WA111-철근콘크리트구조 벽 500mm_BW5
단면형상 정의 - 단면형상: 수직
Pset_QuantityTakeOff - Reference: WA111-철근콘크리트구조 벽 500mm_BW5; sets with these values: 2
Pset_WallCommon - LoadBearing: yes; ExtendToStructure: no; Reference: WA111-철근콘크리트구조 벽 500mm_BW5
Name (기본 벽:WA111-철근콘크리트구조 벽 500mm_BW5:...) | 길이 (mm) | 면적 (m2) | 체적 (m3)
2815701 | 6950 | 40.87 | 20.069
2816806 | 13450 | 83 | 41.5
5337811 | 6500 | 39.65 | 19.435

# IfcWall: 기본 벽:WA211-시멘트벽돌(일반) 벽 (0.5B) 90mm (2)
Type - PredefinedType: STANDARD; Material: KBIMS-시멘트 벽돌 90 mm
Type - ID 데이터 - 단가: 0; 유형 이름: WA211-시멘트벽돌(일반) 벽 (0.5B) 90mm
Type - 그래픽 - 거친 축척 채우기 색상: 0
Type - 기타 - 카테고리: 벽; KBIMS-부위코드: E24; 불연성재료: 불연재료; 조달청표준공사코드: AFA111010000; 패밀리 이름: 기본 벽
Type - 시공 - 기능: 외부; 끝단부 마무리: 없음; 인서트 부위 마무리: 마무리하지 않음; 폭: 90 mm
Type - 재료 및 마감재 - 구조 재료: KBIMS-시멘트 벽돌
Type - 해석 특성 - 거칠기: 1; 열 저항(R): 0.125; 열 전달 계수(U): 8 kg/K/s3; 열 질량: 136.62; 흡수율: 9290.3
Type - Pset_WallCommon - IsExternal: yes; ThermalTransmittance: 8 kg/K/s3
공정 - 생성 공정: 새 구성
구속조건 - 베이스 간격띄우기: 0 mm; 매스와 관련됨: no; 룸 경계: yes; 베이스 확장 거리: 0 mm; 벽 베이스가 부착됩니다.: no; 상단 간격띄우기: 0 mm; 상단 확장 거리: 0 mm; 위치선: 벽 중심선; 상단이 부착됩니다.: no
구조 - 구조: no; 구조적 용도: 비교좌장치
기타 - 패밀리: 기본 벽; 유형: WA211-시멘트벽돌(일반) 벽 (0.5B) 90mm; 유형 ID: 6839214; 패밀리 및 유형: 기본 벽: WA211-시멘트벽돌(일반) 벽 (0.5B) 90mm
단면형상 정의 - 단면형상: 수직
Pset_QuantityTakeOff - Reference: WA211-시멘트벽돌(일반) 벽 (0.5B) 90mm; sets with these values: 2
Pset_WallCommon - LoadBearing: no; ExtendToStructure: no; Reference: WA211-시멘트벽돌(일반) 벽 (0.5B) 90mm
Name (기본 벽:WA211-시멘트벽돌(일반) 벽 (0.5B) 90mm:...) | In | 베이스 구속조건 | 상단 구속조건 | 미연결 높이 (mm) | 길이 (mm) | 면적 (m2) | 체적 (m3)
5343893 | 지하2층 | 지하2층 | 상위 레벨: 지하1층 | 4000 | 5055 | 6.53355 | 0.58802
5354237 | 지상 3층 | 지상 3층 | 상위 레벨: 지상 4층 | 4100 | 2594.97 | 3.4513 | 0.310428 | ID 데이터 - 해설: SSD

# IfcWall: 기본 벽:WA313-화강석잔다듬 벽 (30, 건식50) 80mm (4)
Type - PredefinedType: STANDARD; Material: KBIMS-화강석 잔다듬 80 mm
Type - ID 데이터 - 단가: 0; 유형 이름: WA313-화강석잔다듬 벽 (30, 건식50) 80mm
Type - 그래픽 - 거친 축척 채우기 색상: 0
Type - 기타 - 카테고리: 벽; KBIMS-부위코드: E24; 불연성재료: 불연재료; 조달청표준공사코드: AMB161A; 패밀리 이름: 기본 벽
Type - 시공 - 기능: 외부; 끝단부 마무리: 없음; 인서트 부위 마무리: 마무리하지 않음; 폭: 80 mm
Type - 해석 특성 - 거칠기: 1; 흡수율: 9290.3
Type - Pset_WallCommon - IsExternal: yes
공정 - 생성 공정: 새 구성
구속조건 - 매스와 관련됨: no; 룸 경계: yes; 베이스 확장 거리: 0 mm; 벽 베이스가 부착됩니다.: no; 상단 확장 거리: 0 mm; 상단이 부착됩니다.: no; 위치선: 마감면:외부
구조 - 구조: no; 구조적 용도: 비교좌장치
기타 - 패밀리: 기본 벽; 유형: WA313-화강석잔다듬 벽 (30, 건식50) 80mm; 유형 ID: 7431676; 패밀리 및 유형: 기본 벽: WA313-화강석잔다듬 벽 (30, 건식50) 80mm
단면형상 정의 - 단면형상: 수직
Pset_QuantityTakeOff - Reference: WA313-화강석잔다듬 벽 (30, 건식50) 80mm; sets with these values: 2
Pset_WallCommon - LoadBearing: no; ExtendToStructure: no; Reference: WA313-화강석잔다듬 벽 (30, 건식50) 80mm
Name (기본 벽:WA313-화강석잔다듬 벽 (30, 건식50) 80mm:...) | In | 상단 간격띄우기 (mm) | 베이스 구속조건 | 상단 구속조건 | 미연결 높이 (mm) | 베이스 간격띄우기 (mm) | 길이 (mm) | 면적 (m2) | 체적 (m3)
2831143 | 지상 1층 | 0 | 지상 1층 | 상위 레벨: 지상 2층 | 6300 | -1500 | 28780 | 52.5513 | 4.20411
2831273 | 지상 1층 | 0 | 지상 1층 | 상위 레벨: 지상 2층 | 6900 | -2100 | 10745 | 71.5501 | 5.72401
2835457 | 지상 3층 | -1400 | 지상 3층 | 상위 레벨: 지상 4층 | 2700 | 0 | 10815 | 4.67406 | 0.373925
3118771 | 지상 1층 | 0 | 지상 1층 | 상위 레벨: 지상 2층 | 4800 | 0 | 21480 | 36.6145 | 2.92916

# IfcWall: 기본 벽:WA731-DRY WALL(C50, GS12.5mm) (1겹한면, GW50mm) 62.5mm (3)
Type - PredefinedType: STANDARD; Material: KBIMS-DRY WALL 12.5 mm, KBIMS-경량철골벽틀 50 mm
Type - ID 데이터 - 단가: 0; 유형 이름: WA731-DRY WALL(C50, GS12.5mm) (1겹한면, GW50mm) 62.5mm
Type - 그래픽 - 거친 축척 채우기 색상: 0
Type - 기타 - 카테고리: 벽; KBIMS-부위코드: E24; 경계벽: yes; 불연성재료: 불연재료; 조달청표준공사코드: AOC700010000; 패밀리 이름: 기본 벽
Type - 시공 - 기능: 내부; 끝단부 마무리: 없음; 인서트 부위 마무리: 마무리하지 않음; 폭: 62.5 mm
Type - 해석 특성 - 거칠기: 1; 열 저항(R): 0.0192308; 열 전달 계수(U): 52 kg/K/s3; 열 질량: 11.55; 흡수율: 9290.3
Type - Pset_WallCommon - IsExternal: no; ThermalTransmittance: 52 kg/K/s3
공정 - 생성 공정: 새 구성
구속조건 - 베이스 간격띄우기: 0 mm; 매스와 관련됨: no; 룸 경계: yes; 베이스 확장 거리: 0 mm; 벽 베이스가 부착됩니다.: no; 상단 확장 거리: 0 mm; 상단이 부착됩니다.: no; 위치선: 구조체 면:내부
구조 - 구조: no; 구조적 용도: 비교좌장치
기타 - 패밀리: 기본 벽; 유형: WA731-DRY WALL(C50, GS12.5mm) (1겹한면, GW50mm) 62.5mm; 유형 ID: 6840292; 패밀리 및 유형: 기본 벽: WA731-DRY WALL(C50, GS12.5mm) (1겹한면, GW50mm) 62.5mm
단면형상 정의 - 단면형상: 수직
Pset_QuantityTakeOff - Reference: WA731-DRY WALL(C50, GS12.5mm) (1겹한면, GW50mm) 62.5mm; sets with these values: 2
Pset_WallCommon - LoadBearing: no; ExtendToStructure: no; Reference: WA731-DRY WALL(C50, GS12.5mm) (1겹한면, GW50mm) 62.5mm
Name (기본 벽:WA731-DRY WALL(C50, GS12.5mm) (1겹한면, GW50mm) 62.5mm:...) | In | 베이스 구속조건 | 상단 구속조건 | 미연결 높이 (mm) | 상단 간격띄우기 (mm) | 길이 (mm) | 면적 (m2) | 체적 (m3)
2835392 | 지상 6층 | 지상 6층 | 상위 레벨: 지상 7층 | 3100 | -1000 | 13530 | 41.5726 | 2.59829
2835400 | 지상 7층 | 지상 7층 | 상위 레벨: 지상 8층 | 3100 | -1000 | 13530.6 | 41.5726 | 2.59829
2835416 | 지상 9층 | 지상 9층 | 상위 레벨: 지상 10층 | 3200 | -1300 | 13530 | 42.9139 | 2.68212

# IfcWall: 옥상 두겁10:옥상 두겁, 옥상 두겁10:옥상 두겁:6548447
In: 옥탑층
Type - Material: KBIMS-복합 패널
Type - ID 데이터 - 유형 이름: 옥상 두겁
Type - 기타 - 카테고리: 일반 모델; 패밀리 이름: 옥상 두겁10
Type - Pset_WallCommon - IsExternal: no
공정 - 생성 공정: 새 구성
구속조건 - 가까운 요소로 이동: no; 레벨로부터의 높이: 0 mm
기타 - 유형: 옥상 두겁; 유형 ID: 6548445; 패밀리: 옥상 두겁10; 패밀리 및 유형: 옥상 두겁10: 옥상 두겁
치수 - 면적: 0.001596 m2; 체적: 0.00632016 m3
Pset_QuantityTakeOff - Reference: 옥상 두겁; sets with these values: 2
Pset_WallCommon - Reference: 옥상 두겁

# IfcWall: 옥상 두겁11:옥상 두겁, 옥상 두겁11:옥상 두겁:6548471
In: 옥탑층
Type - Material: KBIMS-복합 패널
Type - ID 데이터 - 유형 이름: 옥상 두겁
Type - 기타 - 카테고리: 일반 모델; 패밀리 이름: 옥상 두겁11
Type - Pset_WallCommon - IsExternal: no
공정 - 생성 공정: 새 구성
구속조건 - 가까운 요소로 이동: no; 레벨로부터의 높이: 0 mm
기타 - 유형: 옥상 두겁; 유형 ID: 6548469; 패밀리: 옥상 두겁11; 패밀리 및 유형: 옥상 두겁11: 옥상 두겁
치수 - 면적: 0.001596 m2; 체적: 0.00632016 m3
Pset_QuantityTakeOff - Reference: 옥상 두겁; sets with these values: 2
Pset_WallCommon - Reference: 옥상 두겁

# IfcWall: 옥상 두겁12:옥상 두겁, 옥상 두겁12:옥상 두겁:6548497
In: 옥탑층
Type - Material: KBIMS-복합 패널
Type - ID 데이터 - 유형 이름: 옥상 두겁
Type - 기타 - 카테고리: 일반 모델; 패밀리 이름: 옥상 두겁12
Type - Pset_WallCommon - IsExternal: no
공정 - 생성 공정: 새 구성
구속조건 - 가까운 요소로 이동: no; 레벨로부터의 높이: 0 mm
기타 - 유형: 옥상 두겁; 유형 ID: 6548495; 패밀리: 옥상 두겁12; 패밀리 및 유형: 옥상 두겁12: 옥상 두겁
치수 - 면적: 0.001596 m2; 체적: 0.00632016 m3
Pset_QuantityTakeOff - Reference: 옥상 두겁; sets with these values: 2
Pset_WallCommon - Reference: 옥상 두겁

# IfcWall: 옥상 두겁13:옥상 두겁, 옥상 두겁13:옥상 두겁:6548523
In: 옥탑층
Type - Material: KBIMS-복합 패널
Type - ID 데이터 - 유형 이름: 옥상 두겁
Type - 기타 - 카테고리: 일반 모델; 패밀리 이름: 옥상 두겁13
Type - Pset_WallCommon - IsExternal: no
공정 - 생성 공정: 새 구성
구속조건 - 가까운 요소로 이동: no; 레벨로부터의 높이: 0 mm
기타 - 유형: 옥상 두겁; 유형 ID: 6548521; 패밀리: 옥상 두겁13; 패밀리 및 유형: 옥상 두겁13: 옥상 두겁
치수 - 면적: 0.001596 m2; 체적: 0.00632016 m3
Pset_QuantityTakeOff - Reference: 옥상 두겁; sets with these values: 2
Pset_WallCommon - Reference: 옥상 두겁

# IfcWall: 옥상 두겁14:옥상 두겁, 옥상 두겁14:옥상 두겁:6548549
In: 옥탑층
Type - Material: KBIMS-복합 패널
Type - ID 데이터 - 유형 이름: 옥상 두겁
Type - 기타 - 카테고리: 일반 모델; 패밀리 이름: 옥상 두겁14
Type - Pset_WallCommon - IsExternal: no
공정 - 생성 공정: 새 구성
구속조건 - 가까운 요소로 이동: no; 레벨로부터의 높이: 0 mm
기타 - 유형: 옥상 두겁; 유형 ID: 6548547; 패밀리: 옥상 두겁14; 패밀리 및 유형: 옥상 두겁14: 옥상 두겁
치수 - 면적: 0.001596 m2; 체적: 0.00632016 m3
Pset_QuantityTakeOff - Reference: 옥상 두겁; sets with these values: 2
Pset_WallCommon - Reference: 옥상 두겁

# IfcWall: 옥상 두겁15:옥상 두겁, 옥상 두겁15:옥상 두겁:6548575
In: 옥탑층
Type - Material: KBIMS-복합 패널
Type - ID 데이터 - 유형 이름: 옥상 두겁
Type - 기타 - 카테고리: 일반 모델; 패밀리 이름: 옥상 두겁15
Type - Pset_WallCommon - IsExternal: no
공정 - 생성 공정: 새 구성
구속조건 - 가까운 요소로 이동: no; 레벨로부터의 높이: 0 mm
기타 - 유형: 옥상 두겁; 유형 ID: 6548573; 패밀리: 옥상 두겁15; 패밀리 및 유형: 옥상 두겁15: 옥상 두겁
치수 - 면적: 0.001596 m2; 체적: 0.00632016 m3
Pset_QuantityTakeOff - Reference: 옥상 두겁; sets with these values: 2
Pset_WallCommon - Reference: 옥상 두겁

# IfcWall: 옥상 두겁16:옥상 두겁, 옥상 두겁16:옥상 두겁:6548616
In: 옥탑층
Type - Material: KBIMS-복합 패널
Type - ID 데이터 - 유형 이름: 옥상 두겁
Type - 기타 - 카테고리: 일반 모델; 패밀리 이름: 옥상 두겁16
Type - Pset_WallCommon - IsExternal: no
공정 - 생성 공정: 새 구성
구속조건 - 가까운 요소로 이동: no; 레벨로부터의 높이: 0 mm
기타 - 유형: 옥상 두겁; 유형 ID: 6548614; 패밀리: 옥상 두겁16; 패밀리 및 유형: 옥상 두겁16: 옥상 두겁
치수 - 면적: 0.001596 m2; 체적: 0.00632016 m3
Pset_QuantityTakeOff - Reference: 옥상 두겁; sets with these values: 2
Pset_WallCommon - Reference: 옥상 두겁

# IfcWall: 옥상 두겁17:옥상 두겁, 옥상 두겁17:옥상 두겁:6548642
In: 옥탑층
Type - Material: KBIMS-복합 패널
Type - ID 데이터 - 유형 이름: 옥상 두겁
Type - 기타 - 카테고리: 일반 모델; 패밀리 이름: 옥상 두겁17
Type - Pset_WallCommon - IsExternal: no
공정 - 생성 공정: 새 구성
구속조건 - 가까운 요소로 이동: no; 레벨로부터의 높이: 0 mm
기타 - 유형: 옥상 두겁; 유형 ID: 6548640; 패밀리: 옥상 두겁17; 패밀리 및 유형: 옥상 두겁17: 옥상 두겁
치수 - 면적: 0.001596 m2; 체적: 0.00632016 m3
Pset_QuantityTakeOff - Reference: 옥상 두겁; sets with these values: 2
Pset_WallCommon - Reference: 옥상 두겁

# IfcWall: 옥상 두겁18:옥상 두겁, 옥상 두겁18:옥상 두겁:6548668
In: 옥탑층
Type - Material: KBIMS-복합 패널
Type - ID 데이터 - 유형 이름: 옥상 두겁
Type - 기타 - 카테고리: 일반 모델; 패밀리 이름: 옥상 두겁18
Type - Pset_WallCommon - IsExternal: no
공정 - 생성 공정: 새 구성
구속조건 - 가까운 요소로 이동: no; 레벨로부터의 높이: 0 mm
기타 - 유형: 옥상 두겁; 유형 ID: 6548666; 패밀리: 옥상 두겁18; 패밀리 및 유형: 옥상 두겁18: 옥상 두겁
치수 - 면적: 0.001596 m2; 체적: 0.00632016 m3
Pset_QuantityTakeOff - Reference: 옥상 두겁; sets with these values: 2
Pset_WallCommon - Reference: 옥상 두겁

# IfcWall: 옥상 두겁19:옥상 두겁, 옥상 두겁19:옥상 두겁:6548696
In: 옥탑층
Type - Material: KBIMS-복합 패널
Type - ID 데이터 - 유형 이름: 옥상 두겁
Type - 기타 - 카테고리: 일반 모델; 패밀리 이름: 옥상 두겁19
Type - Pset_WallCommon - IsExternal: no
공정 - 생성 공정: 새 구성
구속조건 - 가까운 요소로 이동: no; 레벨로부터의 높이: 0 mm
기타 - 유형: 옥상 두겁; 유형 ID: 6548694; 패밀리: 옥상 두겁19; 패밀리 및 유형: 옥상 두겁19: 옥상 두겁
치수 - 면적: 0.001596 m2; 체적: 0.00632016 m3
Pset_QuantityTakeOff - Reference: 옥상 두겁; sets with these values: 2
Pset_WallCommon - Reference: 옥상 두겁

# IfcWall: 옥상 두겁1:옥상 두겁, 옥상 두겁1:옥상 두겁:5536617
In: 옥탑층
Type - Material: KBIMS-복합 패널
Type - ID 데이터 - 유형 이름: 옥상 두겁
Type - 기타 - 카테고리: 일반 모델; 패밀리 이름: 옥상 두겁1
Type - Pset_WallCommon - IsExternal: no
공정 - 생성 공정: 새 구성
구속조건 - 가까운 요소로 이동: no
기타 - 유형: 옥상 두겁; 유형 ID: 5536615; 패밀리: 옥상 두겁1; 패밀리 및 유형: 옥상 두겁1: 옥상 두겁
치수 - 면적: 0.1022 m2; 체적: 0.0715401 m3
Pset_QuantityTakeOff - Reference: 옥상 두겁; sets with these values: 2
Pset_WallCommon - Reference: 옥상 두겁

# IfcWall: 옥상 두겁20:옥상 두겁, 옥상 두겁20:옥상 두겁:6548722
In: 옥탑층
Type - Material: KBIMS-복합 패널
Type - ID 데이터 - 유형 이름: 옥상 두겁
Type - 기타 - 카테고리: 일반 모델; 패밀리 이름: 옥상 두겁20
Type - Pset_WallCommon - IsExternal: no
공정 - 생성 공정: 새 구성
구속조건 - 가까운 요소로 이동: no; 레벨로부터의 높이: 0 mm
기타 - 유형: 옥상 두겁; 유형 ID: 6548720; 패밀리: 옥상 두겁20; 패밀리 및 유형: 옥상 두겁20: 옥상 두겁
치수 - 면적: 0.001596 m2; 체적: 0.00632016 m3
Pset_QuantityTakeOff - Reference: 옥상 두겁; sets with these values: 2
Pset_WallCommon - Reference: 옥상 두겁

# IfcWall: 옥상 두겁21:옥상 두겁, 옥상 두겁21:옥상 두겁:6548748
In: 옥탑층
Type - Material: KBIMS-복합 패널
Type - ID 데이터 - 유형 이름: 옥상 두겁
Type - 기타 - 카테고리: 일반 모델; 패밀리 이름: 옥상 두겁21
Type - Pset_WallCommon - IsExternal: no
공정 - 생성 공정: 새 구성
구속조건 - 가까운 요소로 이동: no; 레벨로부터의 높이: 0 mm
기타 - 유형: 옥상 두겁; 유형 ID: 6548746; 패밀리: 옥상 두겁21; 패밀리 및 유형: 옥상 두겁21: 옥상 두겁
치수 - 면적: 0.001596 m2; 체적: 0.00632016 m3
Pset_QuantityTakeOff - Reference: 옥상 두겁; sets with these values: 2
Pset_WallCommon - Reference: 옥상 두겁

# IfcWall: 옥상 두겁22:옥상 두겁, 옥상 두겁22:옥상 두겁:6548772
In: 옥탑층
Type - Material: KBIMS-복합 패널
Type - ID 데이터 - 유형 이름: 옥상 두겁
Type - 기타 - 카테고리: 일반 모델; 패밀리 이름: 옥상 두겁22
Type - Pset_WallCommon - IsExternal: no
공정 - 생성 공정: 새 구성
구속조건 - 가까운 요소로 이동: no; 레벨로부터의 높이: 0 mm
기타 - 유형: 옥상 두겁; 유형 ID: 6548770; 패밀리: 옥상 두겁22; 패밀리 및 유형: 옥상 두겁22: 옥상 두겁
치수 - 면적: 0.001596 m2; 체적: 0.00632016 m3
Pset_QuantityTakeOff - Reference: 옥상 두겁; sets with these values: 2
Pset_WallCommon - Reference: 옥상 두겁

# IfcWall: 옥상 두겁23:옥상 두겁, 옥상 두겁23:옥상 두겁:6548955
In: 옥탑층
Type - Material: KBIMS-복합 패널
Type - ID 데이터 - 유형 이름: 옥상 두겁
Type - 기타 - 카테고리: 일반 모델; 패밀리 이름: 옥상 두겁23
Type - Pset_WallCommon - IsExternal: no
공정 - 생성 공정: 새 구성
구속조건 - 가까운 요소로 이동: no
기타 - 유형: 옥상 두겁; 유형 ID: 6548953; 패밀리: 옥상 두겁23; 패밀리 및 유형: 옥상 두겁23: 옥상 두겁
치수 - 면적: 450.505 m2; 체적: 0.90101 m3
Pset_QuantityTakeOff - Reference: 옥상 두겁; sets with these values: 2
Pset_WallCommon - Reference: 옥상 두겁

# IfcWall: 옥상 두겁24:옥상 두겁, 옥상 두겁24:옥상 두겁:6549352
In: 옥탑층
Type - Material: KBIMS-복합 패널
Type - ID 데이터 - 유형 이름: 옥상 두겁
Type - 기타 - 카테고리: 일반 모델; 패밀리 이름: 옥상 두겁24
Type - Pset_WallCommon - IsExternal: no
공정 - 생성 공정: 새 구성
구속조건 - 가까운 요소로 이동: no
기타 - 유형: 옥상 두겁; 유형 ID: 6549350; 패밀리: 옥상 두겁24; 패밀리 및 유형: 옥상 두겁24: 옥상 두겁
치수 - 면적: 0.100025 m2; 체적: 0.0700177 m3
Pset_QuantityTakeOff - Reference: 옥상 두겁; sets with these values: 2
Pset_WallCommon - Reference: 옥상 두겁

# IfcWall: 옥상 두겁25:옥상 두겁, 옥상 두겁25:옥상 두겁:6549653
In: 옥탑층
Type - Material: KBIMS-복합 패널
Type - ID 데이터 - 유형 이름: 옥상 두겁
Type - 기타 - 카테고리: 일반 모델; 패밀리 이름: 옥상 두겁25
Type - Pset_WallCommon - IsExternal: no
공정 - 생성 공정: 새 구성
구속조건 - 가까운 요소로 이동: no; 레벨로부터의 높이: 0 mm
기타 - 유형: 옥상 두겁; 유형 ID: 6549651; 패밀리: 옥상 두겁25; 패밀리 및 유형: 옥상 두겁25: 옥상 두겁
치수 - 면적: 0.001596 m2; 체적: 0.00632016 m3
Pset_QuantityTakeOff - Reference: 옥상 두겁; sets with these values: 2
Pset_WallCommon - Reference: 옥상 두겁

# IfcWall: 옥상 두겁26:옥상 두겁, 옥상 두겁26:옥상 두겁:6550008
In: 옥탑층
Type - Material: KBIMS-복합 패널
Type - ID 데이터 - 유형 이름: 옥상 두겁
Type - 기타 - 카테고리: 일반 모델; 패밀리 이름: 옥상 두겁26
Type - Pset_WallCommon - IsExternal: no
공정 - 생성 공정: 새 구성
구속조건 - 가까운 요소로 이동: no; 레벨로부터의 높이: 0 mm
기타 - 유형: 옥상 두겁; 유형 ID: 6550006; 패밀리: 옥상 두겁26; 패밀리 및 유형: 옥상 두겁26: 옥상 두겁
치수 - 면적: 0.000701 m2; 체적: 0.00326666 m3
Pset_QuantityTakeOff - Reference: 옥상 두겁; sets with these values: 2
Pset_WallCommon - Reference: 옥상 두겁

# IfcWall: 옥상 두겁27:옥상 두겁, 옥상 두겁27:옥상 두겁:6550729
In: 옥탑층
Type - Material: KBIMS-복합 패널
Type - ID 데이터 - 유형 이름: 옥상 두겁
Type - 기타 - 카테고리: 일반 모델; 패밀리 이름: 옥상 두겁27
Type - Pset_WallCommon - IsExternal: no
공정 - 생성 공정: 새 구성
구속조건 - 가까운 요소로 이동: no; 레벨로부터의 높이: 0 mm
기타 - 유형: 옥상 두겁; 유형 ID: 6550727; 패밀리: 옥상 두겁27; 패밀리 및 유형: 옥상 두겁27: 옥상 두겁
치수 - 면적: 0.0109274 m2; 체적: 0.0432725 m3
Pset_QuantityTakeOff - Reference: 옥상 두겁; sets with these values: 2
Pset_WallCommon - Reference: 옥상 두겁

# IfcWall: 옥상 두겁28:옥상 두겁, 옥상 두겁28:옥상 두겁:6550889
In: 옥탑층
Type - Material: KBIMS-복합 패널
Type - ID 데이터 - 유형 이름: 옥상 두겁
Type - 기타 - 카테고리: 일반 모델; 패밀리 이름: 옥상 두겁28
Type - Pset_WallCommon - IsExternal: no
공정 - 생성 공정: 새 구성
구속조건 - 가까운 요소로 이동: no; 레벨로부터의 높이: 0 mm
기타 - 유형: 옥상 두겁; 유형 ID: 6550887; 패밀리: 옥상 두겁28; 패밀리 및 유형: 옥상 두겁28: 옥상 두겁
치수 - 면적: 0.0011511 m2; 체적: 0.000805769 m3
Pset_QuantityTakeOff - Reference: 옥상 두겁; sets with these values: 2
Pset_WallCommon - Reference: 옥상 두겁

# IfcWall: 옥상 두겁29:옥상 두겁, 옥상 두겁29:옥상 두겁:6551142
In: 옥탑층
Type - Material: KBIMS-복합 패널
Type - ID 데이터 - 유형 이름: 옥상 두겁
Type - 기타 - 카테고리: 일반 모델; 패밀리 이름: 옥상 두겁29
Type - Pset_WallCommon - IsExternal: no
공정 - 생성 공정: 새 구성
구속조건 - 가까운 요소로 이동: no; 레벨로부터의 높이: 0 mm
기타 - 유형: 옥상 두겁; 유형 ID: 6551140; 패밀리: 옥상 두겁29; 패밀리 및 유형: 옥상 두겁29: 옥상 두겁
치수 - 면적: 0.000701 m2; 체적: 0.00277596 m3
Pset_QuantityTakeOff - Reference: 옥상 두겁; sets with these values: 2
Pset_WallCommon - Reference: 옥상 두겁

# IfcWall: 옥상 두겁2:옥상 두겁, 옥상 두겁2:옥상 두겁:6547277
In: 옥탑층
Type - Material: KBIMS-복합 패널
Type - ID 데이터 - 유형 이름: 옥상 두겁
Type - 기타 - 카테고리: 일반 모델; 패밀리 이름: 옥상 두겁2
Type - Pset_WallCommon - IsExternal: no
공정 - 생성 공정: 새 구성
구속조건 - 가까운 요소로 이동: no; 레벨로부터의 높이: 0 mm
기타 - 유형: 옥상 두겁; 유형 ID: 6547275; 패밀리: 옥상 두겁2; 패밀리 및 유형: 옥상 두겁2: 옥상 두겁
치수 - 면적: 0.001596 m2; 체적: 0.00632016 m3
Pset_QuantityTakeOff - Reference: 옥상 두겁; sets with these values: 2
Pset_WallCommon - Reference: 옥상 두겁

# IfcWall: 옥상 두겁3:옥상 두겁, 옥상 두겁3:옥상 두겁:6548208
In: 옥탑층
Type - Material: KBIMS-복합 패널
Type - ID 데이터 - 유형 이름: 옥상 두겁
Type - 기타 - 카테고리: 일반 모델; 패밀리 이름: 옥상 두겁3
Type - Pset_WallCommon - IsExternal: no
공정 - 생성 공정: 새 구성
구속조건 - 가까운 요소로 이동: no; 레벨로부터의 높이: 0 mm
기타 - 유형: 옥상 두겁; 유형 ID: 6548206; 패밀리: 옥상 두겁3; 패밀리 및 유형: 옥상 두겁3: 옥상 두겁
치수 - 면적: 0.001596 m2; 체적: 0.00632016 m3
Pset_QuantityTakeOff - Reference: 옥상 두겁; sets with these values: 2
Pset_WallCommon - Reference: 옥상 두겁

# IfcWall: 옥상 두겁4:옥상 두겁, 옥상 두겁4:옥상 두겁:6548238
In: 옥탑층
Type - Material: KBIMS-복합 패널
Type - ID 데이터 - 유형 이름: 옥상 두겁
Type - 기타 - 카테고리: 일반 모델; 패밀리 이름: 옥상 두겁4
Type - Pset_WallCommon - IsExternal: no
공정 - 생성 공정: 새 구성
구속조건 - 가까운 요소로 이동: no; 레벨로부터의 높이: 0 mm
기타 - 유형: 옥상 두겁; 유형 ID: 6548236; 패밀리: 옥상 두겁4; 패밀리 및 유형: 옥상 두겁4: 옥상 두겁
치수 - 면적: 0.001596 m2; 체적: 0.00632016 m3
Pset_QuantityTakeOff - Reference: 옥상 두겁; sets with these values: 2
Pset_WallCommon - Reference: 옥상 두겁

# IfcWall: 옥상 두겁5:옥상 두겁, 옥상 두겁5:옥상 두겁:6548266
In: 옥탑층
Type - Material: KBIMS-복합 패널
Type - ID 데이터 - 유형 이름: 옥상 두겁
Type - 기타 - 카테고리: 일반 모델; 패밀리 이름: 옥상 두겁5
Type - Pset_WallCommon - IsExternal: no
공정 - 생성 공정: 새 구성
구속조건 - 가까운 요소로 이동: no; 레벨로부터의 높이: 0 mm
기타 - 유형: 옥상 두겁; 유형 ID: 6548264; 패밀리: 옥상 두겁5; 패밀리 및 유형: 옥상 두겁5: 옥상 두겁
치수 - 면적: 0.001596 m2; 체적: 0.00632016 m3
Pset_QuantityTakeOff - Reference: 옥상 두겁; sets with these values: 2
Pset_WallCommon - Reference: 옥상 두겁

# IfcWall: 옥상 두겁6:옥상 두겁, 옥상 두겁6:옥상 두겁:6548292
In: 옥탑층
Type - Material: KBIMS-복합 패널
Type - ID 데이터 - 유형 이름: 옥상 두겁
Type - 기타 - 카테고리: 일반 모델; 패밀리 이름: 옥상 두겁6
Type - Pset_WallCommon - IsExternal: no
공정 - 생성 공정: 새 구성
구속조건 - 가까운 요소로 이동: no; 레벨로부터의 높이: 0 mm
기타 - 유형: 옥상 두겁; 유형 ID: 6548290; 패밀리: 옥상 두겁6; 패밀리 및 유형: 옥상 두겁6: 옥상 두겁
치수 - 면적: 0.001596 m2; 체적: 0.00632016 m3
Pset_QuantityTakeOff - Reference: 옥상 두겁; sets with these values: 2
Pset_WallCommon - Reference: 옥상 두겁

# IfcWall: 옥상 두겁7:옥상 두겁, 옥상 두겁7:옥상 두겁:6548320
In: 옥탑층
Type - Material: KBIMS-복합 패널
Type - ID 데이터 - 유형 이름: 옥상 두겁
Type - 기타 - 카테고리: 일반 모델; 패밀리 이름: 옥상 두겁7
Type - Pset_WallCommon - IsExternal: no
공정 - 생성 공정: 새 구성
구속조건 - 가까운 요소로 이동: no; 레벨로부터의 높이: 0 mm
기타 - 유형: 옥상 두겁; 유형 ID: 6548318; 패밀리: 옥상 두겁7; 패밀리 및 유형: 옥상 두겁7: 옥상 두겁
치수 - 면적: 0.001596 m2; 체적: 0.00632016 m3
Pset_QuantityTakeOff - Reference: 옥상 두겁; sets with these values: 2
Pset_WallCommon - Reference: 옥상 두겁

# IfcWall: 옥상 두겁8:옥상 두겁, 옥상 두겁8:옥상 두겁:6548363
In: 옥탑층
Type - Material: KBIMS-복합 패널
Type - ID 데이터 - 유형 이름: 옥상 두겁
Type - 기타 - 카테고리: 일반 모델; 패밀리 이름: 옥상 두겁8
Type - Pset_WallCommon - IsExternal: no
공정 - 생성 공정: 새 구성
구속조건 - 가까운 요소로 이동: no; 레벨로부터의 높이: 0 mm
기타 - 유형: 옥상 두겁; 유형 ID: 6548361; 패밀리: 옥상 두겁8; 패밀리 및 유형: 옥상 두겁8: 옥상 두겁
치수 - 면적: 0.00224998 m2; 체적: 0.00890991 m3
Pset_QuantityTakeOff - Reference: 옥상 두겁; sets with these values: 2
Pset_WallCommon - Reference: 옥상 두겁

# IfcWall: 옥상 두겁9:옥상 두겁, 옥상 두겁9:옥상 두겁:6548423
In: 옥탑층
Type - Material: KBIMS-복합 패널
Type - ID 데이터 - 유형 이름: 옥상 두겁
Type - 기타 - 카테고리: 일반 모델; 패밀리 이름: 옥상 두겁9
Type - Pset_WallCommon - IsExternal: no
공정 - 생성 공정: 새 구성
구속조건 - 가까운 요소로 이동: no; 레벨로부터의 높이: 0 mm
기타 - 유형: 옥상 두겁; 유형 ID: 6548421; 패밀리: 옥상 두겁9; 패밀리 및 유형: 옥상 두겁9: 옥상 두겁
치수 - 면적: 0.001596 m2; 체적: 0.00632016 m3
Pset_QuantityTakeOff - Reference: 옥상 두겁; sets with these values: 2
Pset_WallCommon - Reference: 옥상 두겁

# IfcWall: 파라펫1:파라펫, 파라펫1:파라펫:2996264
In: 옥탑층
Type - Material: KBIMS-화강석 혹두기
Type - ID 데이터 - 유형 이름: 파라펫
Type - 기타 - 카테고리: 벽; KBIMS-부위코드: E24; 조달청표준공사코드: AJC103100000; 패밀리 이름: 파라펫1
Type - Pset_WallCommon - IsExternal: no
공정 - 생성 공정: 새 구성
구속조건 - 룸 경계: yes; 가까운 요소로 이동: no; 레벨로부터의 높이: 0 mm
구조 - 보강 철근 피복: 보강 철근 피복 1 <25 mm>
기타 - 유형: 파라펫; 유형 ID: 2996262; 패밀리: 파라펫1; 패밀리 및 유형: 파라펫1: 파라펫
치수 - 면적: 3.458 m2; 체적: 0.27664 m3
Pset_QuantityTakeOff - Reference: 파라펫; sets with these values: 2
Pset_WallCommon - Reference: 파라펫

# IfcWall: 파라펫2:파라펫, 파라펫2:파라펫:2999811
In: 옥탑층
Type - Material: KBIMS-화강석 혹두기
Type - ID 데이터 - 유형 이름: 파라펫
Type - 기타 - 카테고리: 벽; KBIMS-부위코드: E24; 조달청표준공사코드: AJC103100000; 패밀리 이름: 파라펫2
Type - Pset_WallCommon - IsExternal: no
공정 - 생성 공정: 새 구성
구속조건 - 룸 경계: yes; 가까운 요소로 이동: no; 레벨로부터의 높이: 0 mm
구조 - 보강 철근 피복: 보강 철근 피복 1 <25 mm>
기타 - 유형: 파라펫; 유형 ID: 2999809; 패밀리: 파라펫2; 패밀리 및 유형: 파라펫2: 파라펫
치수 - 면적: 8.62024 m2; 체적: 0.689619 m3
Pset_QuantityTakeOff - Reference: 파라펫; sets with these values: 2
Pset_WallCommon - Reference: 파라펫

# IfcWall: 파라펫:파라펫, 파라펫:파라펫:2991721
In: 옥탑층
Type - Material: KBIMS-화강석 혹두기
Type - ID 데이터 - 유형 이름: 파라펫
Type - 기타 - 카테고리: 벽; KBIMS-부위코드: E24; 조달청표준공사코드: AJC103100000; 패밀리 이름: 파라펫
Type - Pset_WallCommon - IsExternal: no
공정 - 생성 공정: 새 구성
구속조건 - 룸 경계: yes; 가까운 요소로 이동: no; 레벨로부터의 높이: 0 mm
구조 - 보강 철근 피복: 보강 철근 피복 1 <25 mm>
기타 - 유형: 파라펫; 유형 ID: 2991719; 패밀리: 파라펫; 패밀리 및 유형: 파라펫: 파라펫
치수 - 면적: 40.0796 m2; 체적: 3.20637 m3
Pset_QuantityTakeOff - Reference: 파라펫; sets with these values: 2
Pset_WallCommon - Reference: 파라펫

# IfcWallStandardCase: 기본 벽:(복합)A1-32-06A+WA111+A1-33-01B_수성+철콘+화장실 (4)
In: 지상 10층
Type - PredefinedType: STANDARD; Material: WA611-수성페인트 (내부) 벽 (3회) 1 mm, WA551-시멘트모르타르 (내부) 벽 18mm 16 mm, WA555-콘크리트면정리 벽 (내부) 1 mm, KBIMS-콘크리트 200 mm, WA551-시멘트모르타르 (내부) 벽 18mm 22 mm, WA352-도기질타일 벽 200x200 8 mm
Type - ID 데이터 - 단가: 0; 유형 마크: CW1; 유형 이름: (복합)A1-32-06A+WA111+A1-33-01B_수성+철콘+화장실
Type - 그래픽 - 거친 축척 채우기 색상: 0
Type - 기타 - 내화구조여부: yes; 주요구조부여부: yes; 카테고리: 벽; KBIMS-부위코드: E275; 조달청표준공사코드: ADANC132110000+AGA113100000+AGA441100000+AMA112C+AGA114400000; 패밀리 이름: 기본 벽
Type - 시공 - 기능: 외부; 끝단부 마무리: 없음; 인서트 부위 마무리: 마무리하지 않음; 폭: 248 mm
Type - 재료 및 마감재 - 구조 재료: KBIMS-콘크리트
Type - 해석 특성 - 거칠기: 1; 열 저항(R): 0.245707; 열 전달 계수(U): 4.0699 kg/K/s3; 열 질량: 364.08; 흡수율: 9290.3
Type - Pset_WallCommon - IsExternal: yes; ThermalTransmittance: 4.0699 kg/K/s3
BaseQuantities - Height: 5000 mm; Width: 248 mm
공정 - 생성 공정: 새 구성
구속조건 - 베이스 간격띄우기: 0 mm; 매스와 관련됨: no; 룸 경계: yes; 베이스 확장 거리: 0 mm; 벽 베이스가 부착됩니다.: no; 상단 간격띄우기: 0 mm; 상단 확장 거리: 0 mm; 상단이 부착됩니다.: no; 위치선: 구조체 면:외부; 베이스 구속조건: 지상 10층; 상단 구속조건: 상위 레벨: 옥탑층; 미연결 높이: 5000 mm
구조 - 구조: yes; 보강 철근 피복 - 다른 면: 보강 철근 피복 1 <25 mm>; 구조적 용도: 교좌장치; 보강 철근 피복 - 내부 면: 보강 철근 피복 1 <25 mm>; 보강 철근 피복 - 외부 면: 보강 철근 피복 1 <25 mm>
기타 - 패밀리: 기본 벽; 유형: (복합)A1-32-06A+WA111+A1-33-01B_수성+철콘+화장실; 유형 ID: 7717586; 패밀리 및 유형: 기본 벽: (복합)A1-32-06A+WA111+A1-33-01B_수성+철콘+화장실
단면형상 정의 - 단면형상: 수직
Pset_QuantityTakeOff - Reference: (복합)A1-32-06A+WA111+A1-33-01B_수성+철콘+화장실; sets with these values: 2
Pset_WallCommon - LoadBearing: yes; ExtendToStructure: no; Reference: (복합)A1-32-06A+WA111+A1-33-01B_수성+철콘+화장실
Name (기본 벽:(복합)A1-32-06A+WA111+A1-33-01B_수성+철콘+화장실:...) | Length (mm) | GrossFootprintArea (m2) | GrossVolume (m3) | GrossSideArea (m2) | NetSideArea (m2) = 면적 (m2) | NetVolume (m3) = 체적 (m3) | 연관 있음 | 길이 (mm)
2822395 | 5452 | 1.35061 | 6.76048 | 27.26 | 27.26 | 6.75304 | yes | 5760
2822417 | 2817.99 | 0.698862 | 3.49431 | 14.09 | 13.7 | 3.39759 | yes | 2817.99
7723282 | 3390.99 | 0.840966 | 4.20483 | 16.955 | 16.955 | 4.09394 | no | 3390.99
7724061 | 4430 | 1.09864 | 5.4932 | 22.15 | 22.15 | 5.34767 | no | 4430

# IfcWallStandardCase: 기본 벽:(복합)A2-22-02A+A1-32-06A_압출+수성 (6)
In: 지상 10층
Type - PredefinedType: STANDARD; Material: WA240-ALC블록벽 35 mm, WA795-(STEEL)BRACKET 65 mm, WA821-압출스티로폼 벽 (본드붙임, 비중0.03) 50mm 50 mm, WA555-콘크리트면정리 벽 (내부) 1 mm, WA551-시멘트모르타르 (내부) 벽 18mm 16 mm, WA611-수성페인트 (내부) 벽 (3회) 1 mm
Type - ID 데이터 - 단가: 0; 유형 이름: (복합)A2-22-02A+A1-32-06A_압출+수성
Type - 그래픽 - 거친 축척 채우기 색상: 0
Type - 기타 - 카테고리: 벽; KBIMS-부위코드: E24; 불연성재료: 불연재료; 조달청표준공사코드: AFC100+AJM+AOD112322000+ANC132110000+AGA113100000+AGA441100000; 패밀리 이름: 기본 벽
Type - 시공 - 기능: 외부; 끝단부 마무리: 없음; 인서트 부위 마무리: 마무리하지 않음; 폭: 168 mm
Type - 해석 특성 - 거칠기: 1; 열 저항(R): 1.8758; 열 전달 계수(U): 0.533106 kg/K/s3; 열 질량: 31.0364; 흡수율: 9290.3
Type - Pset_WallCommon - IsExternal: yes; ThermalTransmittance: 0.533106 kg/K/s3
BaseQuantities - Width: 168 mm
공정 - 생성 공정: 새 구성
구속조건 - 매스와 관련됨: no; 베이스 확장 거리: 0 mm; 벽 베이스가 부착됩니다.: no; 상단 확장 거리: 0 mm; 상단이 부착됩니다.: no; 베이스 구속조건: 지상 10층; 위치선: 마감면:외부
구조 - 구조: no; 구조적 용도: 비교좌장치
기타 - 패밀리: 기본 벽; 유형: (복합)A2-22-02A+A1-32-06A_압출+수성; 유형 ID: 7718054; 패밀리 및 유형: 기본 벽: (복합)A2-22-02A+A1-32-06A_압출+수성
단면형상 정의 - 단면형상: 수직
Pset_QuantityTakeOff - Reference: (복합)A2-22-02A+A1-32-06A_압출+수성; sets with these values: 2
Pset_WallCommon - LoadBearing: no; ExtendToStructure: no; Reference: (복합)A2-22-02A+A1-32-06A_압출+수성
Name (기본 벽:(복합)A2-22-02A+A1-32-06A_압출+수성:...) | Height (mm) = 미연결 높이 (mm) | Length (mm) | GrossFootprintArea (m2) | GrossVolume (m3) = NetVolume (m3) = 체적 (m3) | GrossSideArea (m2) = NetSideArea (m2) = 면적 (m2) | 룸 경계 | 상단 간격띄우기 (mm) | 상단 구속조건 | 베이스 간격띄우기 (mm) | 길이 (mm)
2835538 | 1400 | 34800 | 5.8464 | 8.18496 | 48.72 | no | 0 | 상위 레벨: 옥탑층 | 3600 | 34716 | ID 데이터 - 해설: A
2835539 | 1400 | 37532 | 6.30538 | 8.82753 | 52.5448 | yes | 0 | 상위 레벨: 옥탑층 | 3600 | 37532
2835540 | 1400 | 28132 | 4.72618 | 6.61665 | 39.3848 | yes | 0 | 상위 레벨: 옥탑층 | 3600 | 28216
5899109 | 600 | 34800 | 5.8464 | 3.50784 | 20.88 | no | 600 | 상위 레벨: 지상 10층 | 0 | 34716 | ID 데이터 - 해설: A
5899110 | 600 | 37532 | 6.30538 | 3.78323 | 22.5192 | yes | 600 | 상위 레벨: 지상 10층 | 0 | 37532
5899111 | 600 | 28132 | 4.72618 | 2.83571 | 16.8792 | yes | 600 | 상위 레벨: 지상 10층 | 0 | 28216

# IfcWallStandardCase: 기본 벽:(복합)A2-22-02A+WA111(200_CW1)+A1-32-06A_압출+철콘+수성, 기본 벽:(복합)A2-22-02A+WA111(200_CW1)+A1-32-06A_압출+철콘+수성:2822387
In: 지상 10층
Type - PredefinedType: STANDARD; Material: WA240-ALC블록벽 35 mm, WA795-(STEEL)BRACKET 65 mm, WA821-압출스티로폼 벽 (본드붙임, 비중0.03) 50mm 50 mm, KBIMS-콘크리트 200 mm, WA555-콘크리트면정리 벽 (내부) 1 mm, WA551-시멘트모르타르 (내부) 벽 18mm 16 mm, WA611-수성페인트 (내부) 벽 (3회) 1 mm
Type - ID 데이터 - 단가: 0; 유형 마크: CW1; 유형 이름: (복합)A2-22-02A+WA111(200_CW1)+A1-32-06A_압출+철콘+수성
Type - 그래픽 - 거친 축척 채우기 색상: 0
Type - 기타 - 내화구조여부: yes; 주요구조부여부: yes; 카테고리: 벽; KBIMS-부위코드: E275; 조달청표준공사코드: AD+AFC100+AJM+AOD112322000+ANC132110000+AGA113100000+AGA441100000; 패밀리 이름: 기본 벽
Type - 시공 - 기능: 외부; 끝단부 마무리: 없음; 인서트 부위 마무리: 마무리하지 않음; 폭: 368 mm
Type - 재료 및 마감재 - 구조 재료: KBIMS-콘크리트
Type - 해석 특성 - 거칠기: 1; 열 저항(R): 2.067; 열 전달 계수(U): 0.483792 kg/K/s3; 열 질량: 333.256; 흡수율: 9290.3
Type - Pset_WallCommon - IsExternal: yes; ThermalTransmittance: 0.483792 kg/K/s3
BaseQuantities - Height: 5000 mm; Length: 2921.01 mm; Width: 368 mm; GrossFootprintArea: 1.07493 m2; GrossVolume: 4.78733 m3; GrossSideArea: 13.009 m2; NetSideArea: 13.009 m2; NetVolume: 4.78733 m3
ID 데이터 - 연관 있음: yes
공정 - 생성 공정: 새 구성
구속조건 - 베이스 간격띄우기: 0 mm; 매스와 관련됨: no; 룸 경계: yes; 베이스 확장 거리: 0 mm; 벽 베이스가 부착됩니다.: no; 상단 간격띄우기: 0 mm; 상단 확장 거리: 0 mm; 상단이 부착됩니다.: no; 위치선: 구조체 면:외부; 미연결 높이: 5000 mm; 베이스 구속조건: 지상 10층; 상단 구속조건: 상위 레벨: 옥탑층
구조 - 구조: yes; 보강 철근 피복 - 다른 면: 보강 철근 피복 1 <25 mm>; 구조적 용도: 교좌장치; 보강 철근 피복 - 내부 면: 보강 철근 피복 1 <25 mm>; 보강 철근 피복 - 외부 면: 보강 철근 피복 1 <25 mm>
기타 - 패밀리: 기본 벽; 유형: (복합)A2-22-02A+WA111(200_CW1)+A1-32-06A_압출+철콘+수성; 유형 ID: 7720991; 패밀리 및 유형: 기본 벽: (복합)A2-22-02A+WA111(200_CW1)+A1-32-06A_압출+철콘+수성
단면형상 정의 - 단면형상: 수직
치수 - 길이: 2803.01 mm; 면적: 13.009 m2; 체적: 4.78733 m3
Pset_QuantityTakeOff - Reference: (복합)A2-22-02A+WA111(200_CW1)+A1-32-06A_압출+철콘+수성; sets with these values: 2
Pset_WallCommon - LoadBearing: yes; ExtendToStructure: no; Reference: (복합)A2-22-02A+WA111(200_CW1)+A1-32-06A_압출+철콘+수성

# IfcWallStandardCase: 기본 벽:(복합)A2-22-02A+WA111(200_W1)+A1-32-06A_금속+철콘+수성 3 (2)
In: 지상 10층
Type - PredefinedType: STANDARD; Material: WA785-금속외장패널 25 mm, WA793-금속 긴결철물 벽 75 mm, WA821-압출스티로폼 벽 (본드붙임, 비중0.03) 50mm 50 mm, KBIMS-콘크리트 200 mm, WA555-콘크리트면정리 벽 (내부) 1 mm, WA551-시멘트모르타르 (내부) 벽 18mm 16 mm, WA611-수성페인트 (내부) 벽 (3회) 1 mm
Type - ID 데이터 - 단가: 0; 유형 마크: W1; 유형 이름: (복합)A2-22-02A+WA111(200_W1)+A1-32-06A_금속+철콘+수성 3
Type - 그래픽 - 거친 축척 채우기 색상: 0
Type - 기타 - 내화구조여부: yes; 주요구조부여부: yes; 카테고리: 벽; KBIMS-부위코드: E275; 조달청표준공사코드: AFC100+AJM+AOD112322000+AD+ANC132110000+AGA113100000+AGA441100000; 패밀리 이름: 기본 벽
Type - 시공 - 기능: 외부; 끝단부 마무리: 없음; 인서트 부위 마무리: 마무리하지 않음; 폭: 368 mm
Type - 재료 및 마감재 - 구조 재료: KBIMS-콘크리트
Type - 해석 특성 - 거칠기: 1; 열 저항(R): 2.067; 열 전달 계수(U): 0.483792 kg/K/s3; 열 질량: 333.256; 흡수율: 9290.3
Type - Pset_WallCommon - IsExternal: yes; ThermalTransmittance: 0.483792 kg/K/s3
BaseQuantities - Height: 5000 mm; Width: 368 mm
ID 데이터 - 연관 있음: yes
공정 - 생성 공정: 새 구성
구속조건 - 베이스 간격띄우기: 0 mm; 매스와 관련됨: no; 룸 경계: yes; 베이스 확장 거리: 0 mm; 벽 베이스가 부착됩니다.: no; 상단 간격띄우기: 0 mm; 상단 확장 거리: 0 mm; 상단이 부착됩니다.: no; 위치선: 구조체 면:외부; 베이스 구속조건: 지상 10층; 상단 구속조건: 상위 레벨: 옥탑층; 미연결 높이: 5000 mm
구조 - 구조: yes; 보강 철근 피복 - 다른 면: 보강 철근 피복 1 <25 mm>; 구조적 용도: 교좌장치; 보강 철근 피복 - 내부 면: 보강 철근 피복 1 <25 mm>; 보강 철근 피복 - 외부 면: 보강 철근 피복 1 <25 mm>
기타 - 패밀리: 기본 벽; 유형: (복합)A2-22-02A+WA111(200_W1)+A1-32-06A_금속+철콘+수성 3; 유형 ID: 7718854; 패밀리 및 유형: 기본 벽: (복합)A2-22-02A+WA111(200_W1)+A1-32-06A_금속+철콘+수성 3
단면형상 정의 - 단면형상: 수직
Pset_QuantityTakeOff - Reference: (복합)A2-22-02A+WA111(200_W1)+A1-32-06A_금속+철콘+수성 3; sets with these values: 2
Pset_WallCommon - LoadBearing: yes; ExtendToStructure: no; Reference: (복합)A2-22-02A+WA111(200_W1)+A1-32-06A_금속+철콘+수성 3
Name (기본 벽:(복합)A2-22-02A+WA111(200_W1)+A1-32-06A_금속+철콘+수성 3:...) | Length (mm) = 길이 (mm) | GrossFootprintArea (m2) | GrossVolume (m3) | GrossSideArea (m2) | NetSideArea (m2) = 면적 (m2) | NetVolume (m3) = 체적 (m3)
2822409 | 1400 | 0.5152 | 2.576 | 7 | 7 | 2.53022
2822429 | 9300.01 | 3.4224 | 17.112 | 46.5 | 42.9 | 15.4831

# IfcWallStandardCase: 기본 벽:(복합)A2-22-02A+WA111(200_W1)+A1-32-06A_압출+철콘+수성 2, 기본 벽:(복합)A2-22-02A+WA111(200_W1)+A1-32-06A_압출+철콘+수성 2:7721671
In: 지상 10층
Type - PredefinedType: STANDARD; Material: WA240-ALC블록벽 35 mm, WA795-(STEEL)BRACKET 65 mm, WA821-압출스티로폼 벽 (본드붙임, 비중0.03) 50mm 50 mm, KBIMS-콘크리트 200 mm, WA555-콘크리트면정리 벽 (내부) 1 mm, WA551-시멘트모르타르 (내부) 벽 18mm 16 mm, WA611-수성페인트 (내부) 벽 (3회) 1 mm
Type - ID 데이터 - 단가: 0; 유형 마크: W1; 유형 이름: (복합)A2-22-02A+WA111(200_W1)+A1-32-06A_압출+철콘+수성 2
Type - 그래픽 - 거친 축척 채우기 색상: 0
Type - 기타 - 내화구조여부: yes; 주요구조부여부: yes; 카테고리: 벽; KBIMS-부위코드: E275; 조달청표준공사코드: AD+AFC100+AJM+AOD112322000+ANC132110000+AGA113100000+AGA441100000; 패밀리 이름: 기본 벽
Type - 시공 - 기능: 외부; 끝단부 마무리: 없음; 인서트 부위 마무리: 마무리하지 않음; 폭: 368 mm
Type - 재료 및 마감재 - 구조 재료: KBIMS-콘크리트
Type - 해석 특성 - 거칠기: 1; 열 저항(R): 2.067; 열 전달 계수(U): 0.483792 kg/K/s3; 열 질량: 333.256; 흡수율: 9290.3
Type - Pset_WallCommon - IsExternal: yes; ThermalTransmittance: 0.483792 kg/K/s3
BaseQuantities - Height: 5000 mm; Length: 13500 mm; Width: 368 mm; GrossFootprintArea: 4.968 m2; GrossVolume: 24.84 m3; GrossSideArea: 67.5 m2; NetSideArea: 63.9 m2; NetVolume: 23.1368 m3
ID 데이터 - 연관 있음: no
공정 - 생성 공정: 새 구성
구속조건 - 베이스 간격띄우기: 0 mm; 매스와 관련됨: no; 룸 경계: yes; 베이스 확장 거리: 0 mm; 벽 베이스가 부착됩니다.: no; 상단 간격띄우기: 0 mm; 상단 확장 거리: 0 mm; 상단이 부착됩니다.: no; 위치선: 구조체 면:외부; 베이스 구속조건: 지상 10층; 상단 구속조건: 상위 레벨: 옥탑층; 미연결 높이: 5000 mm
구조 - 구조: yes; 보강 철근 피복 - 다른 면: 보강 철근 피복 1 <25 mm>; 구조적 용도: 교좌장치; 보강 철근 피복 - 내부 면: 보강 철근 피복 1 <25 mm>; 보강 철근 피복 - 외부 면: 보강 철근 피복 1 <25 mm>
기타 - 패밀리: 기본 벽; 유형: (복합)A2-22-02A+WA111(200_W1)+A1-32-06A_압출+철콘+수성 2; 유형 ID: 7718583; 패밀리 및 유형: 기본 벽: (복합)A2-22-02A+WA111(200_W1)+A1-32-06A_압출+철콘+수성 2
단면형상 정의 - 단면형상: 수직
치수 - 길이: 13500 mm; 면적: 63.9 m2; 체적: 23.1368 m3
Pset_QuantityTakeOff - Reference: (복합)A2-22-02A+WA111(200_W1)+A1-32-06A_압출+철콘+수성 2; sets with these values: 2
Pset_WallCommon - LoadBearing: yes; ExtendToStructure: no; Reference: (복합)A2-22-02A+WA111(200_W1)+A1-32-06A_압출+철콘+수성 2

# IfcWallStandardCase: 기본 벽:(복합)WA111(200_CW1)+A1-32-06A_철콘+수성 (9)
In: 지상 10층
Type - PredefinedType: STANDARD; Material: WA611-수성페인트 (내부) 벽 (3회) 1 mm, WA551-시멘트모르타르 (내부) 벽 18mm 16 mm, WA555-콘크리트면정리 벽 (내부) 1 mm, KBIMS-콘크리트 200 mm, WA555-콘크리트면정리 벽 (내부) 1 mm, WA551-시멘트모르타르 (내부) 벽 18mm 16 mm, WA611-수성페인트 (내부) 벽 (3회) 1 mm
Type - ID 데이터 - 단가: 0; 유형 마크: CW1; 유형 이름: (복합)WA111(200_CW1)+A1-32-06A_철콘+수성
Type - 그래픽 - 거친 축척 채우기 색상: 0
Type - 기타 - 내화구조여부: yes; 주요구조부여부: yes; 카테고리: 벽; KBIMS-부위코드: E275; 조달청표준공사코드: AD+ANC132110000+AGA113100000+AGA441100000; 패밀리 이름: 기본 벽
Type - 시공 - 기능: 외부; 끝단부 마무리: 없음; 인서트 부위 마무리: 마무리하지 않음; 폭: 236 mm
Type - 재료 및 마감재 - 구조 재료: KBIMS-콘크리트
Type - 해석 특성 - 거칠기: 1; 열 저항(R): 0.239097; 열 전달 계수(U): 4.1824 kg/K/s3; 열 질량: 359.148; 흡수율: 9290.3
Type - Pset_WallCommon - IsExternal: yes; ThermalTransmittance: 4.1824 kg/K/s3
BaseQuantities - Width: 236 mm
공정 - 생성 공정: 새 구성
구속조건 - 베이스 간격띄우기: 0 mm; 매스와 관련됨: no; 룸 경계: yes; 베이스 확장 거리: 0 mm; 벽 베이스가 부착됩니다.: no; 상단 간격띄우기: 0 mm; 상단 확장 거리: 0 mm; 상단이 부착됩니다.: no; 베이스 구속조건: 지상 10층; 상단 구속조건: 상위 레벨: 옥탑층; 미연결 높이: 5000 mm
기타 - 패밀리: 기본 벽; 유형: (복합)WA111(200_CW1)+A1-32-06A_철콘+수성; 유형 ID: 7717580; 패밀리 및 유형: 기본 벽: (복합)WA111(200_CW1)+A1-32-06A_철콘+수성
단면형상 정의 - 단면형상: 수직
Pset_QuantityTakeOff - Reference: (복합)WA111(200_CW1)+A1-32-06A_철콘+수성; sets with these values: 2
Pset_WallCommon - ExtendToStructure: no; Reference: (복합)WA111(200_CW1)+A1-32-06A_철콘+수성
Name (기본 벽:(복합)WA111(200_CW1)+A1-32-06A_철콘+수성:...) | Height (mm) | Length (mm) | GrossFootprintArea (m2) | GrossVolume (m3) | GrossSideArea (m2) | NetSideArea (m2) = 면적 (m2) | NetVolume (m3) = 체적 (m3) | 연관 있음 | 위치선 | 구조 = LoadBearing | 보강 철근 피복 - 다른 면 = 보강 철근 피복 - 내부 면 = 보강 철근 피복 - 외부 면 | 구조적 용도 | 길이 (mm)
2822397 | 5000 | 2561.01 | 0.604398 | 3.02199 | 12.805 | 12.805 | 2.93825 | yes | 구조체 면:외부 | yes | 보강 철근 피복 1 <25 mm> | 교좌장치 | 2679.01
2822399 | 5000 | 3169.91 | 0.748099 | 3.74049 | 15.8495 | 15.8495 | 3.74049 | yes | 구조체 면:외부 | yes | 보강 철근 피복 1 <25 mm> | 교좌장치 | 3169.91
2822401 | 5000 | 2730 | 0.64428 | 3.2214 | 13.65 | 13.65 | 3.2214 | yes | 구조체 면:외부 | yes | 보강 철근 피복 1 <25 mm> | 교좌장치 | 2966
2822403 | 5000 | 2481.01 | 0.585518 | 2.92759 | 12.405 | 12.405 | 2.92759 | yes | 구조체 면:외부 | yes | 보강 철근 피복 1 <25 mm> | 교좌장치 | 2717.01
2822405 | 5000 | 5447.01 | 1.28549 | 6.42747 | 27.235 | 26.275 | 6.20091 | yes | 구조체 면:외부 | yes | 보강 철근 피복 1 <25 mm> | 교좌장치 | 5683.01
2822419 | 5000 | 6734 | 1.58922 | 7.94612 | 33.67 | 33.67 | 7.94612 | yes | 구조체 면:외부 | yes | 보강 철근 피복 1 <25 mm> | 교좌장치 | 6740
2822427 | 5000 | 1623 | 0.383028 | 1.91514 | 8.115 | 8.115 | 1.86182 | yes | 구조체 면:외부 | yes | 보강 철근 피복 1 <25 mm> | 교좌장치 | 1623
5903107 | 4850 | 7899.99 | 1.8644 | 9.04233 | 38.315 | 36.425 | 8.59629 |  | 벽 중심선 | no |  | 비교좌장치 | 7965.99
5903108 | 4770 | 4814 | 1.1361 | 5.41922 | 22.9628 | 22.9628 | 5.41922 |  | 벽 중심선 | no |  | 비교좌장치 | 5116

# IfcWallStandardCase: 기본 벽:(복합)WA111(200_CW1)+WA313_철콘+화강석잔다듬, 기본 벽:(복합)WA111(200_CW1)+WA313_철콘+화강석잔다듬:3179053
In: 지상 10층
Type - PredefinedType: STANDARD; Material: KBIMS_콘크리트 200 mm, KBIMS-화강석 잔다듬 80 mm
Type - ID 데이터 - 단가: 0; 유형 마크: CW1; 유형 이름: (복합)WA111(200_CW1)+WA313_철콘+화강석잔다듬
Type - 그래픽 - 거친 축척 채우기 색상: 0
Type - 기타 - 카테고리: 벽; KBIMS-부위코드: E24; 불연성재료: 불연재료; 조달청표준공사코드: AMB161A+AD; 패밀리 이름: 기본 벽
Type - 시공 - 기능: 외부; 끝단부 마무리: 없음; 인서트 부위 마무리: 마무리하지 않음; 폭: 280 mm
Type - 재료 및 마감재 - 구조 재료: KBIMS_콘크리트
Type - 해석 특성 - 거칠기: 1; 흡수율: 9290.3
Type - Pset_WallCommon - IsExternal: yes
BaseQuantities - Height: 5000 mm; Length: 2000 mm; Width: 280 mm; GrossFootprintArea: 0.56 m2; GrossVolume: 2.76296 m3; GrossSideArea: 9.8677 m2; NetSideArea: 9.8677 m2; NetVolume: 2.76296 m3
공정 - 생성 공정: 새 구성
구속조건 - 베이스 간격띄우기: 0 mm; 매스와 관련됨: no; 룸 경계: yes; 베이스 확장 거리: 0 mm; 벽 베이스가 부착됩니다.: no; 상단 간격띄우기: 0 mm; 상단 확장 거리: 0 mm; 상단이 부착됩니다.: no; 베이스 구속조건: 지상 10층; 상단 구속조건: 상위 레벨: 옥탑층; 위치선: 마감면:외부; 미연결 높이: 5000 mm
구조 - 구조: no; 구조적 용도: 비교좌장치
기타 - 패밀리: 기본 벽; 유형: (복합)WA111(200_CW1)+WA313_철콘+화강석잔다듬; 유형 ID: 7719098; 패밀리 및 유형: 기본 벽: (복합)WA111(200_CW1)+WA313_철콘+화강석잔다듬
단면형상 정의 - 단면형상: 수직
치수 - 길이: 2289 mm; 면적: 9.8677 m2; 체적: 2.76296 m3
Pset_QuantityTakeOff - Reference: (복합)WA111(200_CW1)+WA313_철콘+화강석잔다듬; sets with these values: 2
Pset_WallCommon - LoadBearing: no; ExtendToStructure: no; Reference: (복합)WA111(200_CW1)+WA313_철콘+화강석잔다듬

# IfcWallStandardCase: 기본 벽:(복합)WA211+A1-32-06A-시멘트벽돌(일반)+수성 (8)
In: 지상 10층
Type - PredefinedType: STANDARD; Material: WA611-수성페인트 (내부) 벽 (3회) 1 mm, WA551-시멘트모르타르 (내부) 벽 18mm 16 mm, WA555-콘크리트면정리 벽 (내부) 1 mm, KBIMS-시멘트 벽돌 90 mm, WA555-콘크리트면정리 벽 (내부) 1 mm, WA551-시멘트모르타르 (내부) 벽 18mm 16 mm, WA611-수성페인트 (내부) 벽 (3회) 1 mm
Type - ID 데이터 - 단가: 0; 유형 이름: (복합)WA211+A1-32-06A-시멘트벽돌(일반)+수성
Type - 그래픽 - 거친 축척 채우기 색상: 0
Type - 기타 - 카테고리: 벽; KBIMS-부위코드: E24; 불연성재료: 불연재료; 조달청표준공사코드: AFA111010000+ANC132110000+AGA113100000+AGA441100000; 패밀리 이름: 기본 벽
Type - 시공 - 기능: 외부; 끝단부 마무리: 없음; 인서트 부위 마무리: 마무리하지 않음; 폭: 126 mm
Type - 해석 특성 - 거칠기: 1; 열 저항(R): 0.172893; 열 전달 계수(U): 5.78393 kg/K/s3; 열 질량: 193.548; 흡수율: 9290.3
Type - Pset_WallCommon - IsExternal: yes; ThermalTransmittance: 5.78393 kg/K/s3
BaseQuantities - Width: 126 mm
공정 - 생성 공정: 새 구성
구속조건 - 베이스 간격띄우기: 0 mm; 매스와 관련됨: no; 룸 경계: yes; 베이스 확장 거리: 0 mm; 벽 베이스가 부착됩니다.: no; 상단 간격띄우기: 0 mm; 상단 확장 거리: 0 mm; 위치선: 벽 중심선; 상단이 부착됩니다.: no; 베이스 구속조건: 지상 10층; 상단 구속조건: 상위 레벨: 옥탑층; 미연결 높이: 5000 mm
구조 - 구조: no; 구조적 용도: 비교좌장치
기타 - 패밀리: 기본 벽; 유형: (복합)WA211+A1-32-06A-시멘트벽돌(일반)+수성; 유형 ID: 7725005; 패밀리 및 유형: 기본 벽: (복합)WA211+A1-32-06A-시멘트벽돌(일반)+수성
단면형상 정의 - 단면형상: 수직
Pset_QuantityTakeOff - Reference: (복합)WA211+A1-32-06A-시멘트벽돌(일반)+수성; sets with these values: 2
Pset_WallCommon - LoadBearing: no; ExtendToStructure: no; Reference: (복합)WA211+A1-32-06A-시멘트벽돌(일반)+수성
Name (기본 벽:(복합)WA211+A1-32-06A-시멘트벽돌(일반)+수성:...) | Height (mm) | Length (mm) | GrossFootprintArea (m2) | GrossVolume (m3) | GrossSideArea (m2) | NetSideArea (m2) = 면적 (m2) | NetVolume (m3) = 체적 (m3) | 해설 | 길이 (mm)
5356907 | 5000 | 6800.03 | 0.856804 | 4.28402 | 34.0002 | 10.3787 | 1.30771 | SSD | 6800.03
5356908 | 5000 | 6499.25 | 0.818906 | 1.20726 | 9.58139 | 9.58139 | 1.20726 | SSD | 6499.28
5356909 | 5000 | 2485.15 | 0.313128 | 0.458705 | 3.64052 | 3.64052 | 0.458705 | SSD | 2500
5356910 | 5000 | 10000 | 1.26 | 1.86008 | 14.7625 | 14.7625 | 1.86008 | SSD | 10000
5356911 | 5000 | 2313 | 0.291438 | 0.437094 | 3.469 | 3.469 | 0.437094 |  | 2250
5356912 | 4850 | 2599.97 | 0.327596 | 0.478877 | 3.80061 | 3.80061 | 0.478877 | SSD | 2599.97
5356913 | 4850 | 2687.01 | 0.338563 | 0.445564 | 3.53622 | 3.53622 | 0.445564 |  | 2750.01
5909259 | 5000 | 2732 | 0.344232 | 0.51271 | 4.06913 | 4.06913 | 0.507373 | SSD | 2850

# IfcWallStandardCase: 기본 벽:(복합)WA313+WA111(200_CW1)+A1-32-06A_화강석잔다듬+철콘+수성, 기본 벽:(복합)WA313+WA111(200_CW1)+A1-32-06A_화강석잔다듬+철콘+수성:2822425
In: 지상 10층
Type - PredefinedType: STANDARD; Material: KBIMS-화강석 잔다듬 80 mm, KBIMS_콘크리트 200 mm, WA555-콘크리트면정리 벽 (내부) 1 mm, WA551-시멘트모르타르 (내부) 벽 18mm 16 mm, WA611-수성페인트 (내부) 벽 (3회) 1 mm
Type - ID 데이터 - 단가: 0; 유형 마크: CW1; 유형 이름: (복합)WA313+WA111(200_CW1)+A1-32-06A_화강석잔다듬+철콘+수성
Type - 그래픽 - 거친 축척 채우기 색상: 0
Type - 기타 - 카테고리: 벽; KBIMS-부위코드: E24; 불연성재료: 불연재료; 조달청표준공사코드: AMB161A+AD+ANC132110000+AGA113100000+AGA441100000; 패밀리 이름: 기본 벽
Type - 시공 - 기능: 외부; 끝단부 마무리: 없음; 인서트 부위 마무리: 마무리하지 않음; 폭: 298 mm
Type - 재료 및 마감재 - 구조 재료: KBIMS_콘크리트
Type - 해석 특성 - 거칠기: 1; 열 저항(R): 0.0239464; 열 전달 계수(U): 41.76 kg/K/s3; 열 질량: 28.4639; 흡수율: 9290.3
Type - Pset_WallCommon - IsExternal: yes; ThermalTransmittance: 41.76 kg/K/s3
BaseQuantities - Height: 4850 mm; Length: 1820.01 mm; Width: 298 mm; GrossFootprintArea: 0.542363 m2; GrossVolume: 2.63046 m3; GrossSideArea: 8.82704 m2; NetSideArea: 5.77682 m2; NetVolume: 1.72149 m3
ID 데이터 - 연관 있음: yes
공정 - 생성 공정: 새 구성
구속조건 - 베이스 간격띄우기: 0 mm; 매스와 관련됨: no; 룸 경계: yes; 베이스 확장 거리: 0 mm; 벽 베이스가 부착됩니다.: no; 상단 간격띄우기: 0 mm; 상단 확장 거리: 0 mm; 상단이 부착됩니다.: no; 베이스 구속조건: 지상 10층; 상단 구속조건: 상위 레벨: 옥탑층; 위치선: 마감면:외부; 미연결 높이: 5000 mm
구조 - 구조: yes; 보강 철근 피복 - 다른 면: 보강 철근 피복 1 <25 mm>; 구조적 용도: 교좌장치; 보강 철근 피복 - 내부 면: 보강 철근 피복 1 <25 mm>; 보강 철근 피복 - 외부 면: 보강 철근 피복 1 <25 mm>
기타 - 패밀리: 기본 벽; 유형: (복합)WA313+WA111(200_CW1)+A1-32-06A_화강석잔다듬+철콘+수성; 유형 ID: 7719966; 패밀리 및 유형: 기본 벽: (복합)WA313+WA111(200_CW1)+A1-32-06A_화강석잔다듬+철콘+수성
단면형상 정의 - 단면형상: 수직
치수 - 길이: 1835.01 mm; 면적: 5.77682 m2; 체적: 1.72149 m3
Pset_QuantityTakeOff - Reference: (복합)WA313+WA111(200_CW1)+A1-32-06A_화강석잔다듬+철콘+수성; sets with these values: 2
Pset_WallCommon - LoadBearing: yes; ExtendToStructure: no; Reference: (복합)WA313+WA111(200_CW1)+A1-32-06A_화강석잔다듬+철콘+수성

# IfcWallStandardCase: 기본 벽:(복합)WA731+A1-32-06A_수성+칸막이 (6)
In: 지상 10층
Type - PredefinedType: STANDARD; Material: WA611-수성페인트 (내부) 벽 (3회) 1 mm, WA551-시멘트모르타르 (내부) 벽 18mm 16 mm, WA555-콘크리트면정리 벽 (내부) 1 mm, KBIMS-DRY WALL 12.5 mm, KBIMS-경량철골벽틀 50 mm, WA555-콘크리트면정리 벽 (내부) 1 mm, WA551-시멘트모르타르 (내부) 벽 18mm 16 mm, WA611-수성페인트 (내부) 벽 (3회) 1 mm
Type - ID 데이터 - 단가: 0; 유형 이름: (복합)WA731+A1-32-06A_수성+칸막이
Type - 그래픽 - 거친 축척 채우기 색상: 0
Type - 기타 - 카테고리: 벽; 경계벽: yes; KBIMS-부위코드: E24; 불연성재료: 불연재료; 조달청표준공사코드: AOC700010000ANC132110000+AGA113100000+AGA441100000; 패밀리 이름: 기본 벽
Type - 시공 - 기능: 내부; 끝단부 마무리: 없음; 인서트 부위 마무리: 마무리하지 않음; 폭: 98.5 mm
Type - 해석 특성 - 거칠기: 1; 열 저항(R): 0.0671235; 열 전달 계수(U): 14.8979 kg/K/s3; 열 질량: 68.4778; 흡수율: 9290.3
Type - Pset_WallCommon - IsExternal: no; ThermalTransmittance: 14.8979 kg/K/s3
BaseQuantities - Height: 3700 mm; Width: 98.5 mm
공정 - 생성 공정: 새 구성
구속조건 - 베이스 간격띄우기: 0 mm; 매스와 관련됨: no; 룸 경계: yes; 베이스 확장 거리: 0 mm; 벽 베이스가 부착됩니다.: no; 상단 확장 거리: 0 mm; 상단이 부착됩니다.: no; 베이스 구속조건: 지상 10층; 상단 구속조건: 상위 레벨: 옥탑층; 위치선: 마감면:외부; 미연결 높이: 3700 mm; 상단 간격띄우기: -1300 mm
구조 - 구조: no; 구조적 용도: 비교좌장치
기타 - 패밀리: 기본 벽; 유형: (복합)WA731+A1-32-06A_수성+칸막이; 유형 ID: 7717578; 패밀리 및 유형: 기본 벽: (복합)WA731+A1-32-06A_수성+칸막이
단면형상 정의 - 단면형상: 수직
Pset_QuantityTakeOff - Reference: (복합)WA731+A1-32-06A_수성+칸막이; sets with these values: 2
Pset_WallCommon - LoadBearing: no; ExtendToStructure: no; Reference: (복합)WA731+A1-32-06A_수성+칸막이
Name (기본 벽:(복합)WA731+A1-32-06A_수성+칸막이:...) | Length (mm) | GrossFootprintArea (m2) | GrossVolume (m3) = NetVolume (m3) = 체적 (m3) | GrossSideArea (m2) = NetSideArea (m2) = 면적 (m2) | 길이 (mm)
2835423 | 12100 | 1.19185 | 4.40985 | 44.77 | 12100
2835424 | 13369 | 1.31685 | 4.87234 | 49.4654 | 13516
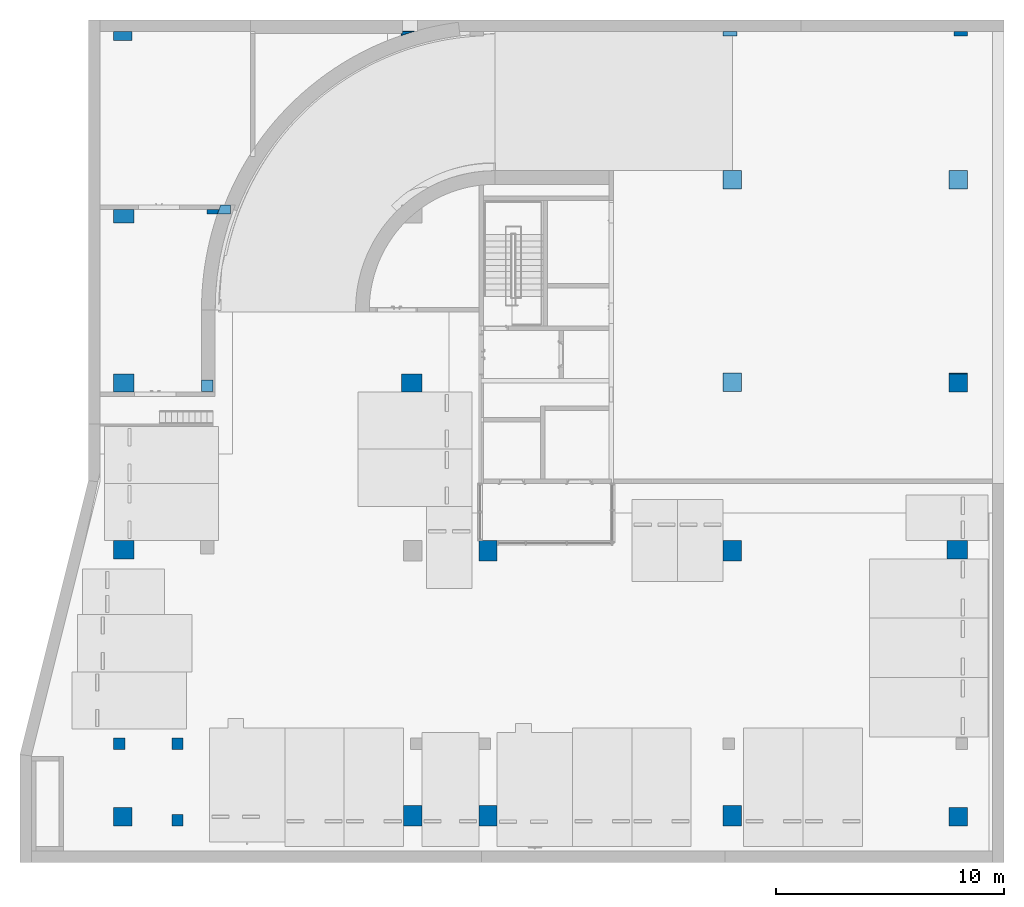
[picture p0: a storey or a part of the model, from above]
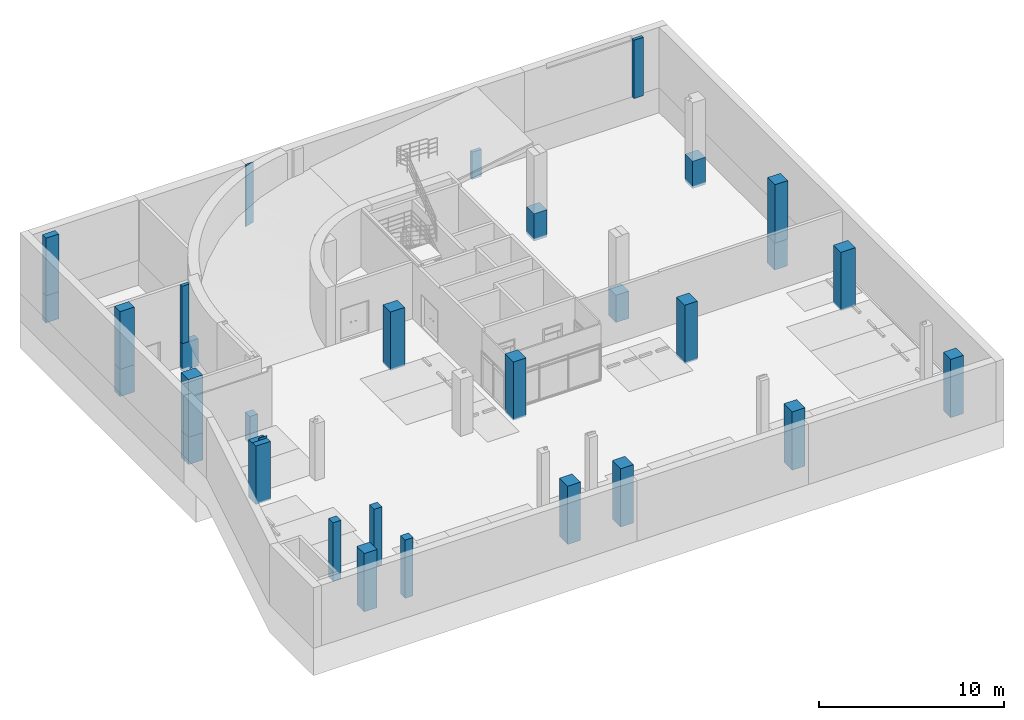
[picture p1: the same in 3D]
Properties of the parts of a building model (IFC2X3), part 35 of 39

# IfcWallStandardCase: 기본 벽:(복합)WA731+A1-32-06A_수성+칸막이 (6)
Name (기본 벽:(복합)WA731+A1-32-06A_수성+칸막이:...) | Length (mm) | GrossFootprintArea (m2) | GrossVolume (m3) = NetVolume (m3) = 체적 (m3) | GrossSideArea (m2) = NetSideArea (m2) = 면적 (m2) | 길이 (mm)
2835425 | 12687 | 1.24967 | 4.62378 | 46.9419 | 12798.2
2835426 | 11100 | 1.09335 | 4.0454 | 41.07 | 11100
2835427 | 7668.99 | 0.755396 | 2.79496 | 28.3753 | 7815.99
2835428 | 11100 | 1.09335 | 4.0454 | 41.07 | 11100

# IfcWallStandardCase: 기본 벽:A1-32-06A-콘크리트면정리, 시멘트모르타르(미장용), 수성페인트(내부) (18mm) (773)
Type - PredefinedType: STANDARD; Material: WA611-수성페인트 (내부) 벽 (3회) 1 mm, WA551-시멘트모르타르 (내부) 벽 18mm 16 mm, WA555-콘크리트면정리 벽 (내부) 1 mm
Type - ID 데이터 - 단가: 0; 유형 이름: A1-32-06A-콘크리트면정리, 시멘트모르타르(미장용), 수성페인트(내부) (18mm)
Type - 그래픽 - 거친 축척 채우기 색상: 0
Type - 기타 - 카테고리: 벽; KBIMS-부위코드: E24; 불연성재료: 불연재료; 조달청표준공사코드: ANC132110000+AGA113100000+AGA441100000; 패밀리 이름: 기본 벽
Type - 시공 - 기능: 외부; 끝단부 마무리: 없음; 인서트 부위 마무리: 마무리하지 않음; 폭: 18 mm
Type - 해석 특성 - 거칠기: 1; 열 저항(R): 0.0239464; 열 전달 계수(U): 41.76 kg/K/s3; 열 질량: 28.4639; 흡수율: 30.48
Type - Pset_WallCommon - IsExternal: yes; ThermalTransmittance: 41.76 kg/K/s3
BaseQuantities - Width: 18 mm
공정 - 생성 공정: 새 구성
구속조건 - 매스와 관련됨: no; 룸 경계: yes; 베이스 확장 거리: 0 mm; 벽 베이스가 부착됩니다.: no; 상단 확장 거리: 0 mm; 위치선: 마감면:내부
구조 - 구조: no; 구조적 용도: 비교좌장치
기타 - 패밀리: 기본 벽; 유형: A1-32-06A-콘크리트면정리, 시멘트모르타르(미장용), 수성페인트(내부) (18mm); 유형 ID: 6825441; 패밀리 및 유형: 기본 벽: A1-32-06A-콘크리트면정리, 시멘트모르타르(미장용), 수성페인트(내부) (18mm)
단면형상 정의 - 단면형상: 수직
Pset_QuantityTakeOff - Reference: A1-32-06A-콘크리트면정리, 시멘트모르타르(미장용), 수성페인트(내부) (18mm); sets with these values: 2
Pset_WallCommon - LoadBearing: no; Reference: A1-32-06A-콘크리트면정리, 시멘트모르타르(미장용), 수성페인트(내부) (18mm)
Name (기본 벽:A1-32-06A-콘크리트면정리, 시멘트모르타르(미장용), 수성페인트(내부) (18mm):...) | In | Height (mm) | Length (mm) | GrossFootprintArea (m2) | GrossVolume (m3) | GrossSideArea (m2) | NetSideArea (m2) | NetVolume (m3) = 체적 (m3) | 베이스 간격띄우기 (mm) | 상단 간격띄우기 (mm) | 상단이 부착됩니다. = ExtendToStructure | 베이스 구속조건 | 미연결 높이 (mm) | 길이 (mm) | 면적 (m2)
7555712 | 지상 2층 | 4500 | 2582.01 | 0.0464762 | 0.209143 | 11.619 | 11.619 | 0.209143 | 0 | 0 | no | 지상 2층 | 4500 | 2582.01 | 11.619 | 구속조건 - 상단 구속조건: 상위 레벨: 지상 3층
7555713 | 지상 2층 | 3200 | 5482 | 0.098676 | 0.315763 | 17.5424 | 15.2324 | 0.274183 | 0 | 0 | no | 지상 2층 | 3200 | 5482 | 15.2324
7555714 | 지상 2층 | 4500 | 2582.01 | 0.0464762 | 0.209143 | 11.619 | 11.619 | 0.209143 | 0 | 0 | no | 지상 2층 | 4500 | 2582.01 | 11.619 | 구속조건 - 상단 구속조건: 상위 레벨: 지상 3층
7555715 | 지상 2층 | 4500 | 5482 | 0.098676 | 0.444042 | 24.669 | 24.669 | 0.444042 | 0 | 0 | no | 지상 2층 | 4500 | 5482 | 24.669 | 구속조건 - 상단 구속조건: 상위 레벨: 지상 3층
7555716 | 지상 2층 | 4500 | 2582.01 | 0.0464762 | 0.209143 | 11.619 | 11.619 | 0.209143 | 0 | 0 | no | 지상 2층 | 4500 | 2582.01 | 11.619 | 구속조건 - 상단 구속조건: 상위 레벨: 지상 3층
7555717 | 지상 2층 | 4500 | 5482 | 0.098676 | 0.444042 | 24.669 | 24.669 | 0.444042 | 0 | 0 | no | 지상 2층 | 4500 | 5482 | 24.669 | 구속조건 - 상단 구속조건: 상위 레벨: 지상 3층
7555718 | 지상 2층 | 4500 | 2582.01 | 0.0464762 | 0.209143 | 11.619 | 7.83904 | 0.141103 | 0 | 0 | no | 지상 2층 | 4500 | 2582.01 | 7.83904 | 구속조건 - 상단 구속조건: 상위 레벨: 지상 3층
7555719 | 지상 2층 | 4500 | 5482 | 0.098676 | 0.444042 | 24.669 | 24.669 | 0.444042 | 0 | 0 | no | 지상 2층 | 4500 | 5482 | 24.669 | 구속조건 - 상단 구속조건: 상위 레벨: 지상 3층
7555720 | 지상 2층 | 3100 | 3282.01 | 0.0590762 | 0.183136 | 10.1742 | 10.1742 | 0.183136 | 80 | -1320 | no | 지상 2층 | 3100 | 3282.01 | 10.1742 | 구속조건 - 상단 구속조건: 상위 레벨: 지상 3층
7555721 | 지상 2층 | 3200 | 2082 | 0.037476 | 0.119923 | 6.6624 | 4.7724 | 0.0859032 | 0 | 0 | no | 지상 2층 | 3200 | 2082 | 4.7724
7555722 | 지상 2층 | 3100 | 3282.01 | 0.0590762 | 0.183136 | 10.1742 | 9.21423 | 0.165856 | 80 | -1320 | no | 지상 2층 | 3100 | 3282.01 | 9.21423 | 구속조건 - 상단 구속조건: 상위 레벨: 지상 3층
7555723 | 지상 2층 | 3100 | 2082 | 0.037476 | 0.0656856 | 3.6492 | 3.6492 | 0.0656856 | 80 | -1320 | no | 지상 2층 | 3100 | 2082 | 3.6492 | 구속조건 - 상단 구속조건: 상위 레벨: 지상 3층
7555728 | 지상 2층 | 3200 | 4850 | 0.0873 | 0.27936 | 15.52 | 15.52 | 0.27936 | 80 | 0 | no | 지상 2층 | 3200 | 4832 | 15.52
7555729 | 지상 2층 | 3100 | 7681.99 | 0.138276 | 0.392745 | 21.8192 | 21.8192 | 0.392745 | 80 | 0 | no | 지상 2층 | 3100 | 7681.99 | 21.8192
7555730 | 지상 2층 | 3100 | 4432 | 0.079776 | 0.247306 | 13.7392 | 11.3392 | 0.204106 | 80 | 0 | no | 지상 2층 | 3100 | 4432 | 11.3392
7555731 | 지상 2층 | 3100 | 400 | 0.0072 | 0.02232 | 1.24 | 1.24 | 0.02232 | 80 | 0 | no | 지상 2층 | 3100 | 400 | 1.24
7555732 | 지상 2층 | 3100 | 400 | 0.0072 | 0.02232 | 1.24 | 1.24 | 0.02232 | 80 | 0 | no | 지상 2층 | 3100 | 400 | 1.24
7555733 | 지상 2층 | 3100 | 2081.99 | 0.0374758 | 0.116175 | 6.45417 | 6.45417 | 0.116175 | 80 | 0 | no | 지상 2층 | 3100 | 2081.99 | 6.45417
7555734 | 지상 2층 | 3100 | 600 | 0.0108 | 0.03348 | 1.86 | 1.86 | 0.03348 | 80 | 0 | no | 지상 2층 | 3100 | 600 | 1.86
7555735 | 지상 2층 | 3100 | 818 | 0.014724 | 0.0456444 | 2.5358 | 2.5358 | 0.0456444 | 80 | 0 | no | 지상 2층 | 3100 | 818 | 2.5358
7555736 | 지상 2층 | 3100 | 600 | 0.0108 | 0.03348 | 1.86 | 1.86 | 0.03348 | 80 | 0 | no | 지상 2층 | 3100 | 600 | 1.86
7555737 | 지상 2층 | 3100 | 4364 | 0.078552 | 0.243511 | 13.5284 | 9.9284 | 0.178711 | 80 | 0 | no | 지상 2층 | 3100 | 4382 | 9.9284
7555738 | 지상 2층 | 80 | 2750 | 0.0495 | 0.00396 | 0.22 | 0.22 | 0.00396 | 80 | 0 | no | 지상 2층 | 3100 | 2850 | 0.22
7555739 | 지상 2층 | 3100 | 5273.01 | 0.0949141 | 0.294234 | 16.3463 | 16.3463 | 0.294234 | 80 | 0 | no | 지상 2층 | 3100 | 5264.01 | 16.3463
7555740 | 지상 2층 | 3100 | 5050 | 0.0909 | 0.28179 | 15.655 | 15.655 | 0.28179 | 80 | 0 | no | 지상 2층 | 3100 | 5050 | 15.655
7555741 | 지상 2층 | 3100 | 7264 | 0.130752 | 0.338371 | 18.7984 | 18.7984 | 0.338371 | 80 | 0 | no | 지상 2층 | 3100 | 7282 | 18.7984
7555742 | 지상 2층 | 3100 | 618 | 0.011124 | 0.0344844 | 1.9158 | 1.9158 | 0.0344844 | 80 | 0 | no | 지상 2층 | 3100 | 609 | 1.9158
7555743 | 지상 2층 | 3100 | 675 | 0.01215 | 0.037665 | 2.0925 | 2.0925 | 0.037665 | 80 | 0 | no | 지상 2층 | 3100 | 746.5 | 2.0925
7555744 | 지상 2층 | 3100 | 13249 | 0.238482 | 0.739295 | 41.0719 | 41.0719 | 0.739295 | 80 | 0 | no | 지상 2층 | 3100 | 13249 | 41.0719
7555745 | 지상 2층 | 3100 | 728.089 | 0.0131056 | 0.0406274 | 2.25708 | 2.25708 | 0.0406274 | 80 | 0 | no | 지상 2층 | 3100 | 719.089 | 2.25708
7555746 | 지상 2층 | 3100 | 737.5 | 0.013275 | 0.0411525 | 2.28625 | 2.28625 | 0.0411525 | 80 | 0 | no | 지상 2층 | 3100 | 737.5 | 2.28625
7555747 | 지상 2층 | 3100 | 11882 | 0.213876 | 0.663016 | 36.8342 | 36.8342 | 0.663016 | 80 | 0 | no | 지상 2층 | 3100 | 11882 | 36.8342
7555748 | 지상 2층 | 3100 | 737.5 | 0.013275 | 0.0411525 | 2.28625 | 2.28625 | 0.0411525 | 80 | 0 | no | 지상 2층 | 3100 | 737.5 | 2.28625
7555749 | 지상 2층 | 3100 | 675 | 0.01215 | 0.037665 | 2.0925 | 2.0925 | 0.037665 | 80 | 0 | no | 지상 2층 | 3100 | 746.5 | 2.0925
7555753 | 지상 2층 | 3100 | 818.035 | 0.0147246 | 0.0456463 | 2.53591 | 2.53591 | 0.0456463 | 80 | 0 | no | 지상 2층 | 3100 | 840.285 | 2.53591
7555754 | 지상 2층 | 3100 | 709.983 | 0.0127797 | 0.039617 | 2.20095 | 2.20095 | 0.039617 | 80 | 0 | no | 지상 2층 | 3100 | 718.983 | 2.20095
7555755 | 지상 2층 | 80 | 6564 | 0.118152 | 0.00945216 | 0.52512 | 0.52512 | 0.00945216 | 80 | 0 | no | 지상 2층 | 3100 | 6582 | 0.52512
7555756 | 지상 2층 | 3100 | 13247.5 | 0.238455 | 0.73921 | 41.0672 | 41.0672 | 0.73921 | 80 | 0 | no | 지상 2층 | 3100 | 13247.5 | 41.0672
7555757 | 지상 2층 | 80 | 6401.47 | 0.115226 | 0.00921811 | 0.512117 | 0.512117 | 0.00921811 | 80 | 0 | no | 지상 2층 | 3100 | 6419.47 | 0.512117
7555758 | 지상 2층 | 3100 | 13285 | 0.23913 | 0.741303 | 41.1835 | 41.1835 | 0.741303 | 80 | 0 | no | 지상 2층 | 3100 | 13347.5 | 41.1835
7555759 | 지상 2층 | 3100 | 818 | 0.014724 | 0.0456444 | 2.5358 | 2.5358 | 0.0456444 | 80 | 0 | no | 지상 2층 | 3100 | 809 | 2.5358
7555760 | 지상 2층 | 3100 | 719.465 | 0.0129504 | 0.0401462 | 2.23034 | 2.23034 | 0.0401462 | 80 | 0 | no | 지상 2층 | 3100 | 737.465 | 2.23034
7555761 | 지상 2층 | 3100 | 755.465 | 0.0135984 | 0.042155 | 2.34194 | 2.34194 | 0.042155 | 80 | 0 | no | 지상 2층 | 3100 | 777.715 | 2.34194
7555762 | 지상 2층 | 3100 | 818 | 0.014724 | 0.0456444 | 2.5358 | 2.5358 | 0.0456444 | 80 | 0 | no | 지상 2층 | 3100 | 818 | 2.5358
7555763 | 지상 2층 | 3100 | 710 | 0.01278 | 0.039618 | 2.201 | 2.201 | 0.039618 | 80 | 0 | no | 지상 2층 | 3100 | 719 | 2.201
7555764 | 지상 2층 | 80 | 2464 | 0.044352 | 0.00354816 | 0.19712 | 0.19712 | 0.00354816 | 80 | 0 | no | 지상 2층 | 3100 | 2482 | 0.19712
7555765 | 지상 2층 | 3100 | 12285 | 0.22113 | 0.685503 | 38.0835 | 38.0835 | 0.685503 | 80 | 0 | no | 지상 2층 | 3100 | 12285 | 38.0835
7555766 | 지상 2층 | 3100 | 693 | 0.012474 | 0.0386694 | 2.1483 | 2.1483 | 0.0386694 | 80 | 0 | no | 지상 2층 | 3100 | 684 | 2.1483
7555767 | 지상 2층 | 3100 | 818 | 0.014724 | 0.0456444 | 2.5358 | 2.5358 | 0.0456444 | 80 | 0 | no | 지상 2층 | 3100 | 818 | 2.5358
7555768 | 지상 2층 | 3100 | 675 | 0.01215 | 0.037665 | 2.0925 | 2.0925 | 0.037665 | 80 | 0 | no | 지상 2층 | 3100 | 684 | 2.0925
7555769 | 지상 2층 | 3100 | 818 | 0.014724 | 0.0456444 | 2.5358 | 2.5358 | 0.0456444 | 80 | 0 | no | 지상 2층 | 3100 | 809 | 2.5358
7555770 | 지상 2층 | 3100 | 675 | 0.01215 | 0.037665 | 2.0925 | 2.0925 | 0.037665 | 80 | 0 | no | 지상 2층 | 3100 | 684 | 2.0925
7555771 | 지상 2층 | 3100 | 755.5 | 0.013599 | 0.0421569 | 2.34205 | 2.34205 | 0.0421569 | 80 | 0 | no | 지상 2층 | 3100 | 777.75 | 2.34205
7555772 | 지상 2층 | 3100 | 710 | 0.01278 | 0.039618 | 2.201 | 2.201 | 0.039618 | 80 | 0 | no | 지상 2층 | 3100 | 710 | 2.201
7555773 | 지상 2층 | 80 | 9863.98 | 0.177552 | 0.0142041 | 0.789119 | 0.789119 | 0.0142041 | 80 | 0 | no | 지상 2층 | 3100 | 9881.98 | 0.789119
7555774 | 지상 2층 | 3100 | 12285 | 0.22113 | 0.685503 | 38.0835 | 38.0835 | 0.685503 | 80 | 0 | no | 지상 2층 | 3100 | 12338.5 | 38.0835
7555775 | 지상 2층 | 3100 | 818 | 0.014724 | 0.0456444 | 2.5358 | 2.5358 | 0.0456444 | 80 | 0 | no | 지상 2층 | 3100 | 809 | 2.5358
7555776 | 지상 2층 | 3100 | 719.653 | 0.0129538 | 0.0401567 | 2.23093 | 2.23093 | 0.0401567 | 80 | 0 | no | 지상 2층 | 3100 | 737.653 | 2.23093
7555777 | 지상 2층 | 3100 | 818.017 | 0.0147243 | 0.0456454 | 2.53585 | 2.53585 | 0.0456454 | 80 | 0 | no | 지상 2층 | 3100 | 777.767 | 2.53585
7555778 | 지상 2층 | 3100 | 709.983 | 0.0127797 | 0.039617 | 2.20095 | 2.20095 | 0.039617 | 80 | 0 | no | 지상 2층 | 3100 | 709.983 | 2.20095
7555779 | 지상 2층 | 80 | 2200 | 0.0396 | 0.003168 | 0.176 | 0.176 | 0.003168 | 80 | 0 | no | 지상 2층 | 3100 | 2200 | 0.176
7555780 | 지상 2층 | 80 | 2622.48 | 0.0472047 | 0.00377638 | 0.209799 | 0.209799 | 0.00377638 | 80 | 0 | no | 지상 2층 | 3100 | 2622.48 | 0.209799
7555781 | 지상 2층 | 3100 | 3905.03 | 0.0702906 | 0.217901 | 12.1056 | 12.1056 | 0.217901 | 80 | 0 | no | 지상 2층 | 3100 | 3887.03 | 12.1056
7555782 | 지상 2층 | 3100 | 600.009 | 0.0108002 | 0.0334805 | 1.86003 | 1.86003 | 0.0334805 | 80 | 0 | no | 지상 2층 | 3100 | 600.009 | 1.86003
7555783 | 지상 2층 | 3100 | 818 | 0.014724 | 0.0456444 | 2.5358 | 2.5358 | 0.0456444 | 80 | 0 | no | 지상 2층 | 3100 | 818 | 2.5358
7555784 | 지상 2층 | 3100 | 600.009 | 0.0108002 | 0.0334805 | 1.86003 | 1.86003 | 0.0334805 | 80 | 0 | no | 지상 2층 | 3100 | 600.009 | 1.86003
7555785 | 지상 2층 | 3100 | 8082 | 0.145476 | 0.450976 | 25.0542 | 25.0542 | 0.450976 | 80 | 0 | no | 지상 2층 | 3100 | 8082 | 25.0542
7555786 | 지상 2층 | 3100 | 600.009 | 0.0108002 | 0.0334805 | 1.86003 | 1.86003 | 0.0334805 | 80 | 0 | no | 지상 2층 | 3100 | 600.009 | 1.86003
7555787 | 지상 2층 | 3100 | 600 | 0.0108 | 0.03348 | 1.86 | 1.86 | 0.03348 | 80 | 0 | no | 지상 2층 | 3100 | 600 | 1.86
7555788 | 지상 2층 | 3100 | 617 | 0.011106 | 0.0344286 | 1.9127 | 1.9127 | 0.0344286 | 80 | 0 | no | 지상 2층 | 3100 | 599 | 1.9127
7555789 | 지상 2층 | 3100 | 674.983 | 0.0121497 | 0.037664 | 2.09245 | 2.09245 | 0.037664 | 80 | 0 | no | 지상 2층 | 3100 | 746.483 | 2.09245
7555790 | 지상 2층 | 3100 | 692.983 | 0.0124737 | 0.0386684 | 2.14825 | 2.14825 | 0.0386684 | 80 | 0 | no | 지상 2층 | 3100 | 746.483 | 2.14825
7555791 | 지상 2층 | 3100 | 818 | 0.014724 | 0.0456444 | 2.5358 | 2.5358 | 0.0456444 | 80 | 0 | no | 지상 2층 | 3100 | 818 | 2.5358
7555792 | 지상 2층 | 3100 | 674.983 | 0.0121497 | 0.037664 | 2.09245 | 2.09245 | 0.037664 | 80 | 0 | no | 지상 2층 | 3100 | 746.483 | 2.09245
7555793 | 지상 2층 | 3100 | 817.991 | 0.0147238 | 0.0456439 | 2.53577 | 2.53577 | 0.0456439 | 80 | 0 | no | 지상 2층 | 3100 | 808.991 | 2.53577
7555794 | 지상 2층 | 3100 | 818 | 0.014724 | 0.0456444 | 2.5358 | 2.5358 | 0.0456444 | 80 | 0 | no | 지상 2층 | 3100 | 818 | 2.5358
7555795 | 지상 2층 | 3100 | 799.983 | 0.0143997 | 0.044639 | 2.47995 | 2.47995 | 0.044639 | 80 | 0 | no | 지상 2층 | 3100 | 808.983 | 2.47995
7555796 | 지상 2층 | 3100 | 817.983 | 0.0147237 | 0.0456434 | 2.53575 | 2.53575 | 0.0456434 | 80 | 0 | no | 지상 2층 | 3100 | 808.983 | 2.53575
7555797 | 지상 2층 | 3100 | 800 | 0.0144 | 0.04464 | 2.48 | 2.48 | 0.04464 | 80 | 0 | no | 지상 2층 | 3100 | 809 | 2.48
7555798 | 지상 2층 | 3100 | 818 | 0.014724 | 0.0456444 | 2.5358 | 2.5358 | 0.0456444 | 80 | 0 | no | 지상 2층 | 3100 | 746.5 | 2.5358
7555799 | 지상 2층 | 3100 | 737.517 | 0.0132753 | 0.0411535 | 2.2863 | 2.2863 | 0.0411535 | 80 | 0 | no | 지상 2층 | 3100 | 737.517 | 2.2863
7555802 | 지상 2층 | 3100 | 11882 | 0.213876 | 0.663016 | 36.8342 | 36.8342 | 0.663016 | 80 | 0 | no | 지상 2층 | 3100 | 11882 | 36.8342
7555803 | 지상 2층 | 3100 | 1202.74 | 0.0216493 | 0.0671128 | 3.72849 | 3.72849 | 0.0671128 | 80 | 0 | no | 지상 2층 | 3100 | 10891 | 3.72849
7555804 | 지상 2층 | 3100 | 10882 | 0.195876 | 0.607216 | 33.7342 | 33.7342 | 0.607216 | 80 | 0 | no | 지상 2층 | 3100 | 10882 | 33.7342
7555805 | 지상 2층 | 3100 | 10864 | 0.195552 | 0.606211 | 33.6784 | 33.6784 | 0.606211 | 80 | 0 | no | 지상 2층 | 3100 | 10882 | 33.6784
7555806 | 지상 2층 | 3100 | 111.574 | 0.00200834 | 0.00622584 | 0.34588 | 0.34588 | 0.00622584 | 80 | 0 | no | 지상 2층 | 3100 | 9082.01 | 0.34588
7555807 | 지상 2층 | 3100 | 7519.49 | 0.135351 | 0.419588 | 23.3104 | 23.3104 | 0.419588 | 80 | 0 | no | 지상 2층 | 3100 | 7528.49 | 23.3104
7555812 | 지상 2층 | 3000 | 2481.98 | 0.0446757 | 0.0981171 | 5.45095 | 5.45095 | 0.0981171 | 80 | -1420 | no | 지상 2층 | 3000 | 2590.98 | 5.45095 | 구속조건 - 상단 구속조건: 상위 레벨: 지상 3층
7555817 | 지상 2층 | 3000 | 11295 | 0.203311 | 0.572132 | 31.7851 | 31.3951 | 0.565112 | 80 | -1420 | no | 지상 2층 | 3000 | 11407 | 31.3951 | 구속조건 - 상단 구속조건: 상위 레벨: 지상 3층
7555819 | 지상 2층 | 3000 | 4618 | 0.083124 | 0.211572 | 11.754 | 11.754 | 0.211572 | 80 | -1420 | no | 지상 2층 | 3000 | 4709 | 11.754 | 구속조건 - 상단 구속조건: 상위 레벨: 지상 3층
7555820 | 지상 2층 | 3000 | 499.991 | 0.00899984 | 0.0269995 | 1.49997 | 1.49997 | 0.0269995 | 80 | -1420 | no | 지상 2층 | 3000 | 608.991 | 1.49997 | 구속조건 - 상단 구속조건: 상위 레벨: 지상 3층
7555821 | 지상 2층 | 3000 | 6703.91 | 0.12067 | 0.343291 | 19.0717 | 19.0717 | 0.343291 | 80 | -1420 | no | 지상 2층 | 3000 | 6703.91 | 19.0717 | 구속조건 - 상단 구속조건: 상위 레벨: 지상 3층
7555822 | 지상 2층 | 3000 | 5918.01 | 0.106524 | 0.218592 | 12.144 | 12.144 | 0.218592 | 80 | -1420 | no | 지상 2층 | 3000 | 5918.01 | 12.144 | 구속조건 - 상단 구속조건: 상위 레벨: 지상 3층
7555823 | 지상 2층 | 3000 | 14953.9 | 0.26917 | 0.713191 | 39.6217 | 39.6217 | 0.713191 | 80 | -1420 | no | 지상 2층 | 3000 | 15062.9 | 39.6217 | 구속조건 - 상단 구속조건: 상위 레벨: 지상 3층
7557723 | 지상 3층 | 4100 | 2582.27 | 0.0464809 | 0.190572 | 10.5873 | 10.5873 | 0.190572 | 0 | 0 | no | 지상 3층 | 4100 | 2582.27 | 10.5873 | 구속조건 - 상단 구속조건: 상위 레벨: 지상 4층
7557724 | 지상 3층 | 3200 | 5482 | 0.0972451 | 0.315763 | 17.5424 | 15.2324 | 0.270207 | 0 | 0 | no | 지상 3층 | 3200 | 5482 | 15.2324
7557725 | 지상 3층 | 4100 | 2582.27 | 0.0464809 | 0.190572 | 10.5873 | 10.5873 | 0.190572 | 0 | 0 | no | 지상 3층 | 4100 | 2582.27 | 10.5873 | 구속조건 - 상단 구속조건: 상위 레벨: 지상 4층
7557726 | 지상 3층 | 4100 | 5482 | 0.098676 | 0.404572 | 22.4762 | 22.4762 | 0.404572 | 0 | 0 | no | 지상 3층 | 4100 | 5482 | 22.4762 | 구속조건 - 상단 구속조건: 상위 레벨: 지상 4층
7557727 | 지상 3층 | 4100 | 2582.01 | 0.0464762 | 0.190552 | 10.5862 | 10.5862 | 0.190552 | 0 | 0 | no | 지상 3층 | 4100 | 2582.01 | 10.5862 | 구속조건 - 상단 구속조건: 상위 레벨: 지상 4층
7557728 | 지상 3층 | 4100 | 5482 | 0.098676 | 0.404572 | 22.4762 | 22.4762 | 0.404572 | 0 | 0 | no | 지상 3층 | 4100 | 5482 | 22.4762 | 구속조건 - 상단 구속조건: 상위 레벨: 지상 4층
7557729 | 지상 3층 | 4100 | 2582.01 | 0.0464762 | 0.190552 | 10.5862 | 6.80624 | 0.122512 | 0 | 0 | no | 지상 3층 | 4100 | 2582.01 | 6.80624 | 구속조건 - 상단 구속조건: 상위 레벨: 지상 4층
7557730 | 지상 3층 | 4100 | 5482 | 0.098676 | 0.404572 | 22.4762 | 22.4762 | 0.404572 | 0 | 0 | no | 지상 3층 | 4100 | 5482 | 22.4762 | 구속조건 - 상단 구속조건: 상위 레벨: 지상 4층
7557731 | 지상 3층 | 2980 | 3282.01 | 0.0590762 | 0.176047 | 9.78039 | 9.78039 | 0.176047 | 0 | -1120 | no | 지상 3층 | 2980 | 3282.01 | 9.78039 | 구속조건 - 상단 구속조건: 상위 레벨: 지상 4층
7557732 | 지상 3층 | 3200 | 2082 | 0.037476 | 0.119923 | 6.6624 | 4.7724 | 0.0859032 | 0 | 0 | no | 지상 3층 | 3200 | 2082 | 4.7724
7557733 | 지상 3층 | 2980 | 3282.01 | 0.0590762 | 0.176047 | 9.78039 | 9.78039 | 0.176047 | 0 | -1120 | no | 지상 3층 | 2980 | 3282.01 | 9.78039 | 구속조건 - 상단 구속조건: 상위 레벨: 지상 4층
7557734 | 지상 3층 | 2980 | 2082 | 0.037476 | 0.111678 | 6.20436 | 6.20436 | 0.111678 | 0 | -1120 | no | 지상 3층 | 2980 | 2082 | 6.20436 | 구속조건 - 상단 구속조건: 상위 레벨: 지상 4층
7557739 | 지상 3층 | 2900 | 4850 | 0.0873 | 0.25317 | 14.065 | 14.065 | 0.25317 | 80 | 0 | no | 지상 3층 | 2900 | 4832 | 14.065
7557740 | 지상 3층 | 2900 | 7681.99 | 0.138276 | 0.36698 | 20.3878 | 20.3878 | 0.36698 | 80 | 0 | no | 지상 3층 | 2900 | 7681.99 | 20.3878
7557741 | 지상 3층 | 2900 | 4432 | 0.079776 | 0.23135 | 12.8528 | 10.4528 | 0.18815 | 80 | 0 | no | 지상 3층 | 2900 | 4432 | 10.4528
7557742 | 지상 3층 | 2900 | 400.017 | 0.00720031 | 0.0208809 | 1.16005 | 1.16005 | 0.0208809 | 80 | 0 | no | 지상 3층 | 2900 | 400.017 | 1.16005
7557743 | 지상 3층 | 2900 | 400 | 0.0072 | 0.02088 | 1.16 | 1.16 | 0.02088 | 80 | 0 | no | 지상 3층 | 2900 | 400 | 1.16
7557744 | 지상 3층 | 2900 | 2081.99 | 0.0374758 | 0.10868 | 6.03777 | 6.03777 | 0.10868 | 80 | 0 | no | 지상 3층 | 2900 | 2081.99 | 6.03777
7557745 | 지상 3층 | 2900 | 600 | 0.0108 | 0.03132 | 1.74 | 1.74 | 0.03132 | 80 | 0 | no | 지상 3층 | 2900 | 600 | 1.74
7557746 | 지상 3층 | 2900 | 818 | 0.014724 | 0.0426996 | 2.3722 | 2.3722 | 0.0426996 | 80 | 0 | no | 지상 3층 | 2900 | 818 | 2.3722
7557747 | 지상 3층 | 2900 | 600 | 0.0108 | 0.03132 | 1.74 | 1.74 | 0.03132 | 80 | 0 | no | 지상 3층 | 2900 | 600 | 1.74
7557748 | 지상 3층 | 2900 | 4363.98 | 0.0785517 | 0.2278 | 12.6555 | 9.05555 | 0.163 | 80 | 0 | no | 지상 3층 | 2900 | 4381.98 | 9.05555
7557749 | 지상 3층 | 580 | 2750 | 0.0495 | 0.02871 | 1.595 | 1.595 | 0.02871 | 80 | 0 | no | 지상 3층 | 3200 | 2850 | 1.595
7557750 | 지상 3층 | 2900 | 5310.01 | 0.0955801 | 0.277182 | 15.399 | 15.399 | 0.277182 | 80 | 0 | no | 지상 3층 | 2900 | 5301.01 | 15.399
7557751 | 지상 3층 | 2900 | 5050 | 0.0909 | 0.26361 | 14.645 | 14.645 | 0.26361 | 80 | 0 | no | 지상 3층 | 2900 | 5050 | 14.645
7557753 | 지상 3층 | 2900 | 618 | 0.011124 | 0.0322596 | 1.7922 | 1.7922 | 0.0322596 | 80 | 0 | no | 지상 3층 | 2900 | 609 | 1.7922
7557754 | 지상 3층 | 2900 | 800.017 | 0.0144003 | 0.0417609 | 2.32005 | 2.32005 | 0.0417609 | 80 | 0 | no | 지상 3층 | 2900 | 800.017 | 2.32005
7557755 | 지상 3층 | 2900 | 13392 | 0.241056 | 0.699064 | 38.8369 | 38.8369 | 0.699064 | 80 | 0 | no | 지상 3층 | 2900 | 13392 | 38.8369
7557756 | 지상 3층 | 2900 | 728.107 | 0.0131059 | 0.0380072 | 2.11151 | 2.11151 | 0.0380072 | 80 | 0 | no | 지상 3층 | 2900 | 719.107 | 2.11151
7557757 | 지상 3층 | 2900 | 737.5 | 0.013275 | 0.0384975 | 2.13875 | 2.13875 | 0.0384975 | 80 | 0 | no | 지상 3층 | 2900 | 737.5 | 2.13875
7557758 | 지상 3층 | 2900 | 11882 | 0.213876 | 0.62024 | 34.4578 | 34.4578 | 0.62024 | 80 | 0 | no | 지상 3층 | 2900 | 11882 | 34.4578
7557759 | 지상 3층 | 2900 | 737.5 | 0.013275 | 0.0384975 | 2.13875 | 2.13875 | 0.0384975 | 80 | 0 | no | 지상 3층 | 2900 | 737.5 | 2.13875
7557760 | 지상 3층 | 2900 | 782 | 0.014076 | 0.0408204 | 2.2678 | 2.2678 | 0.0408204 | 80 | 0 | no | 지상 3층 | 2900 | 800 | 2.2678
7557761 | 지상 3층 | 2900 | 800 | 0.0144 | 0.04176 | 2.32 | 2.32 | 0.04176 | 80 | 0 | no | 지상 3층 | 2900 | 791 | 2.32
7557763 | 지상 3층 | 2900 | 11882 | 0.213876 | 0.62024 | 34.4578 | 34.4578 | 0.62024 | 80 | 0 | no | 지상 3층 | 2900 | 11882 | 34.4578
7557764 | 지상 3층 | 2900 | 800 | 0.0144 | 0.04176 | 2.32 | 2.32 | 0.04176 | 80 | 0 | no | 지상 3층 | 2900 | 800 | 2.32
7557765 | 지상 3층 | 2900 | 710 | 0.01278 | 0.037062 | 2.059 | 2.059 | 0.037062 | 80 | 0 | no | 지상 3층 | 2900 | 719 | 2.059
7557767 | 지상 3층 | 2900 | 13374 | 0.240732 | 0.698123 | 38.7846 | 38.7846 | 0.698123 | 80 | 0 | no | 지상 3층 | 2900 | 13383 | 38.7846
7557768 | 지상 3층 | 280 | 6419.5 | 0.115551 | 0.0323543 | 1.79746 | 1.79746 | 0.0323543 | 80 | 0 | no | 지상 3층 | 2900 | 6459.75 | 1.79746
7557769 | 지상 3층 | 2900 | 13410 | 0.24138 | 0.700003 | 38.8891 | 38.8891 | 0.700003 | 80 | 0 | no | 지상 3층 | 2900 | 13401 | 38.8891
7557770 | 지상 3층 | 2900 | 818.244 | 0.0147284 | 0.0427123 | 2.37291 | 2.37291 | 0.0427123 | 80 | 0 | no | 지상 3층 | 2900 | 809.244 | 2.37291
7557771 | 지상 3층 | 2900 | 737.465 | 0.0132744 | 0.0384957 | 2.13865 | 2.13865 | 0.0384957 | 80 | 0 | no | 지상 3층 | 2900 | 737.465 | 2.13865
7557772 | 지상 3층 | 2900 | 755.465 | 0.0135984 | 0.0394353 | 2.19085 | 2.19085 | 0.0394353 | 80 | 0 | no | 지상 3층 | 2900 | 777.715 | 2.19085
7557773 | 지상 3층 | 2900 | 817.756 | 0.0147196 | 0.0426869 | 2.37149 | 2.37149 | 0.0426869 | 80 | 0 | no | 지상 3층 | 2900 | 817.756 | 2.37149
7557774 | 지상 3층 | 2900 | 655 | 0.01179 | 0.034191 | 1.8995 | 1.8995 | 0.034191 | 80 | 0 | no | 지상 3층 | 2900 | 664 | 1.8995
7557776 | 지상 3층 | 2900 | 12305 | 0.22149 | 0.642321 | 35.6845 | 35.6845 | 0.642321 | 80 | 0 | no | 지상 3층 | 2900 | 12305 | 35.6845
7557777 | 지상 3층 | 2900 | 737.5 | 0.013275 | 0.0384975 | 2.13875 | 2.13875 | 0.0384975 | 80 | 0 | no | 지상 3층 | 2900 | 737.5 | 2.13875
7557778 | 지상 3층 | 2900 | 691.983 | 0.0124557 | 0.0361215 | 2.00675 | 2.00675 | 0.0361215 | 80 | 0 | no | 지상 3층 | 2900 | 709.983 | 2.00675
7557779 | 지상 3층 | 280 | 9900.02 | 0.1782 | 0.0498961 | 2.772 | 2.772 | 0.0498961 | 80 | 0 | no | 지상 3층 | 2900 | 9882.02 | 2.772
7557780 | 지상 3층 | 2900 | 12342 | 0.222156 | 0.644251 | 35.7917 | 35.7917 | 0.644251 | 80 | 0 | no | 지상 3층 | 2900 | 12351 | 35.7917
7557781 | 지상 3층 | 2900 | 817.756 | 0.0147196 | 0.0426869 | 2.37149 | 2.37149 | 0.0426869 | 80 | 0 | no | 지상 3층 | 2900 | 777.506 | 2.37149
7557782 | 지상 3층 | 2900 | 692 | 0.012456 | 0.0361224 | 2.0068 | 2.0068 | 0.0361224 | 80 | 0 | no | 지상 3층 | 2900 | 710 | 2.0068
7557784 | 지상 3층 | 280 | 2689.97 | 0.0483932 | 0.0135574 | 0.75319 | 0.75319 | 0.0135501 | 80 | 0 | no | 지상 3층 | 2900 | 2667.72 | 0.75319
7557785 | 지상 3층 | 2900 | 3883.03 | 0.0698946 | 0.202694 | 11.2608 | 11.2608 | 0.202694 | 80 | 0 | no | 지상 3층 | 2900 | 3874.03 | 11.2608
7557786 | 지상 3층 | 2900 | 599.748 | 0.0107955 | 0.0313068 | 1.73927 | 1.73927 | 0.0313068 | 80 | 0 | no | 지상 3층 | 2900 | 599.748 | 1.73927
7557787 | 지상 3층 | 2900 | 818 | 0.014724 | 0.0426996 | 2.3722 | 2.3722 | 0.0426996 | 80 | 0 | no | 지상 3층 | 2900 | 818 | 2.3722
7557788 | 지상 3층 | 2900 | 599.748 | 0.0107955 | 0.0313068 | 1.73927 | 1.73927 | 0.0313068 | 80 | 0 | no | 지상 3층 | 2900 | 599.748 | 1.73927
7557789 | 지상 3층 | 2900 | 8082 | 0.145476 | 0.42188 | 23.4378 | 23.4378 | 0.42188 | 80 | 0 | no | 지상 3층 | 2900 | 8082 | 23.4378
7557790 | 지상 3층 | 2900 | 600.009 | 0.0108002 | 0.0313205 | 1.74003 | 1.74003 | 0.0313205 | 80 | 0 | no | 지상 3층 | 2900 | 600.009 | 1.74003
7557791 | 지상 3층 | 2900 | 600 | 0.0108 | 0.03132 | 1.74 | 1.74 | 0.03132 | 80 | 0 | no | 지상 3층 | 2900 | 709 | 1.74
7557792 | 지상 3층 | 2900 | 618 | 0.011124 | 0.0322596 | 1.7922 | 1.7922 | 0.0322596 | 80 | 0 | no | 지상 3층 | 2900 | 709 | 1.7922
7557793 | 지상 3층 | 2900 | 799.983 | 0.0143997 | 0.0417591 | 2.31995 | 2.31995 | 0.0417591 | 80 | 0 | no | 지상 3층 | 2900 | 858.983 | 2.31995
7557794 | 지상 3층 | 2900 | 818 | 0.014724 | 0.0426996 | 2.3722 | 2.3722 | 0.0426996 | 80 | 0 | no | 지상 3층 | 2900 | 884 | 2.3722
7557795 | 지상 3층 | 2900 | 818 | 0.014724 | 0.0426996 | 2.3722 | 2.3722 | 0.0426996 | 80 | 0 | no | 지상 3층 | 2900 | 818 | 2.3722
7557796 | 지상 3층 | 2900 | 800 | 0.0144 | 0.04176 | 2.32 | 2.32 | 0.04176 | 80 | 0 | no | 지상 3층 | 2900 | 884 | 2.32
7557797 | 지상 3층 | 2900 | 768.244 | 0.0138284 | 0.0401023 | 2.22791 | 2.22791 | 0.0401023 | 80 | 0 | no | 지상 3층 | 2900 | 759.244 | 2.22791
7557798 | 지상 3층 | 2900 | 818 | 0.014724 | 0.0426996 | 2.3722 | 2.3722 | 0.0426996 | 80 | 0 | no | 지상 3층 | 2900 | 818 | 2.3722
7557799 | 지상 3층 | 2900 | 800.244 | 0.0144044 | 0.0417727 | 2.32071 | 2.32071 | 0.0417727 | 80 | 0 | no | 지상 3층 | 2900 | 809.244 | 2.32071
7557804 | 지상 3층 | 2900 | 11864 | 0.213552 | 0.619301 | 34.4056 | 34.4056 | 0.619301 | 80 | 0 | no | 지상 3층 | 2900 | 11882 | 34.4056
7557806 | 지상 3층 | 2900 | 10882 | 0.195876 | 0.56804 | 31.5578 | 31.5578 | 0.56804 | 80 | 0 | no | 지상 3층 | 2900 | 10882 | 31.5578
7557807 | 지상 3층 | 2900 | 10864 | 0.195552 | 0.567101 | 31.5056 | 31.5056 | 0.567101 | 80 | 0 | no | 지상 3층 | 2900 | 10882 | 31.5056
7558527 | 지상 3층 | 2900 | 800 | 0.0144 | 0.04176 | 2.32 | 2.32 | 0.04176 | 80 | 0 | no | 지상 3층 | 2900 | 840.25 | 2.32
7561218 | 지상 4층 | 4100 | 2582.01 | 0.0464762 | 0.190552 | 10.5862 | 10.5862 | 0.190552 | 0 | 0 | no | 지상 4층 | 4100 | 2582.01 | 10.5862 | 구속조건 - 상단 구속조건: 상위 레벨: 지상 5층
7561219 | 지상 4층 | 2900 | 5482 | 0.098676 | 0.28616 | 15.8978 | 13.5878 | 0.24458 | 0 | 0 | no | 지상 4층 | 2900 | 5482 | 13.5878
7561220 | 지상 4층 | 4100 | 2582.01 | 0.0464762 | 0.190552 | 10.5862 | 10.5862 | 0.190552 | 0 | 0 | no | 지상 4층 | 4100 | 2582.01 | 10.5862 | 구속조건 - 상단 구속조건: 상위 레벨: 지상 5층
7561221 | 지상 4층 | 4100 | 5482 | 0.098676 | 0.404572 | 22.4762 | 22.4762 | 0.404572 | 0 | 0 | no | 지상 4층 | 4100 | 5482 | 22.4762 | 구속조건 - 상단 구속조건: 상위 레벨: 지상 5층
7561222 | 지상 4층 | 4100 | 2582.01 | 0.0464762 | 0.190552 | 10.5862 | 10.5862 | 0.190552 | 0 | 0 | no | 지상 4층 | 4100 | 2582.01 | 10.5862 | 구속조건 - 상단 구속조건: 상위 레벨: 지상 5층
7561223 | 지상 4층 | 4100 | 5482 | 0.098676 | 0.404572 | 22.4762 | 22.4762 | 0.404572 | 0 | 0 | no | 지상 4층 | 4100 | 5482 | 22.4762 | 구속조건 - 상단 구속조건: 상위 레벨: 지상 5층
7561224 | 지상 4층 | 4100 | 2582.01 | 0.0464762 | 0.190552 | 10.5862 | 6.80624 | 0.122512 | 0 | 0 | no | 지상 4층 | 4100 | 2582.01 | 6.80624 | 구속조건 - 상단 구속조건: 상위 레벨: 지상 5층
7561225 | 지상 4층 | 4100 | 5482 | 0.098676 | 0.404572 | 22.4762 | 22.4762 | 0.404572 | 0 | 0 | no | 지상 4층 | 4100 | 5482 | 22.4762 | 구속조건 - 상단 구속조건: 상위 레벨: 지상 5층
7561226 | 지상 4층 | 2980 | 3282.64 | 0.0590875 | 0.176081 | 9.78227 | 9.78227 | 0.176081 | 0 | -1120 | no | 지상 4층 | 2980 | 3283.27 | 9.78227 | 구속조건 - 상단 구속조건: 상위 레벨: 지상 5층
7561227 | 지상 4층 | 2900 | 2082 | 0.037476 | 0.10868 | 6.0378 | 4.1478 | 0.0746604 | 0 | 0 | no | 지상 4층 | 2900 | 2082 | 4.1478
7561228 | 지상 4층 | 2980 | 3282.64 | 0.0590875 | 0.176081 | 9.78227 | 8.82227 | 0.158801 | 0 | -1120 | no | 지상 4층 | 2980 | 3282.64 | 8.82227 | 구속조건 - 상단 구속조건: 상위 레벨: 지상 5층
7561229 | 지상 4층 | 2980 | 2082 | 0.037476 | 0.111678 | 6.20436 | 3.39936 | 0.0611885 | 0 | -1120 | no | 지상 4층 | 2980 | 2082 | 3.39936 | 구속조건 - 상단 구속조건: 상위 레벨: 지상 5층
7561234 | 지상 4층 | 2900 | 7400 | 0.1332 | 0.38628 | 21.46 | 19.06 | 0.34308 | 80 | 0 | no | 지상 4층 | 2900 | 7436 | 19.06
7561235 | 지상 4층 | 2900 | 400 | 0.0072 | 0.02088 | 1.16 | 1.16 | 0.02088 | 80 | 0 | no | 지상 4층 | 2900 | 400 | 1.16
7561236 | 지상 4층 | 2900 | 400 | 0.0072 | 0.02088 | 1.16 | 1.16 | 0.02088 | 80 | 0 | no | 지상 4층 | 2900 | 400 | 1.16
7561237 | 지상 4층 | 2900 | 2082.01 | 0.0374762 | 0.108681 | 6.03783 | 6.03783 | 0.108681 | 80 | 0 | no | 지상 4층 | 2900 | 2082.01 | 6.03783
7561238 | 지상 4층 | 2900 | 600 | 0.0108 | 0.03132 | 1.74 | 1.74 | 0.03132 | 80 | 0 | no | 지상 4층 | 2900 | 600 | 1.74
7561239 | 지상 4층 | 2900 | 818 | 0.014724 | 0.0426996 | 2.3722 | 2.3722 | 0.0426996 | 80 | 0 | no | 지상 4층 | 2900 | 818 | 2.3722
7561240 | 지상 4층 | 2900 | 600 | 0.0108 | 0.03132 | 1.74 | 1.74 | 0.03132 | 80 | 0 | no | 지상 4층 | 2900 | 600 | 1.74
7561241 | 지상 4층 | 2900 | 11864 | 0.213552 | 0.6193 | 34.4055 | 30.8055 | 0.5545 | 80 | 0 | no | 지상 4층 | 2900 | 11882 | 30.8055
7561242 | 지상 4층 | 2900 | 18 | 0.000324 | 0.0009396 | 0.0522 | 0.0522 | 0.0009396 | 80 | 0 | no | 지상 4층 | 2900 | 9 | 0.0522
7561243 | 지상 4층 | 2900 | 818 | 0.014724 | 0.0426996 | 2.3722 | 2.3722 | 0.0426996 | 80 | 0 | no | 지상 4층 | 2900 | 800 | 2.3722
7561244 | 지상 4층 | 2900 | 13500 | 0.243 | 0.7047 | 39.15 | 39.15 | 0.7047 | 80 | 0 | no | 지상 4층 | 2900 | 13500 | 39.15
7561245 | 지상 4층 | 2900 | 729 | 0.013122 | 0.0380538 | 2.1141 | 2.1141 | 0.0380538 | 80 | 0 | no | 지상 4층 | 2900 | 720 | 2.1141
7561246 | 지상 4층 | 2900 | 737.5 | 0.013275 | 0.0384975 | 2.13875 | 2.13875 | 0.0384975 | 80 | 0 | no | 지상 4층 | 2900 | 737.5 | 2.13875
7561247 | 지상 4층 | 2900 | 11882 | 0.213876 | 0.620241 | 34.4579 | 34.4579 | 0.620241 | 80 | 0 | no | 지상 4층 | 2900 | 11882 | 34.4579
7561248 | 지상 4층 | 2900 | 737.5 | 0.013275 | 0.0384975 | 2.13875 | 2.13875 | 0.0384975 | 80 | 0 | no | 지상 4층 | 2900 | 737.5 | 2.13875
7561249 | 지상 4층 | 2900 | 781.983 | 0.0140757 | 0.0408195 | 2.26775 | 2.26775 | 0.0408195 | 80 | 0 | no | 지상 4층 | 2900 | 799.983 | 2.26775
7561253 | 지상 4층 | 2900 | 817.999 | 0.014724 | 0.0426996 | 2.3722 | 2.3722 | 0.0426996 | 80 | 0 | no | 지상 4층 | 2900 | 840.249 | 2.3722
7561254 | 지상 4층 | 2900 | 711 | 0.012798 | 0.0371142 | 2.0619 | 2.0619 | 0.0371142 | 80 | 0 | no | 지상 4층 | 2900 | 720 | 2.0619
7561255 | 지상 4층 | 2900 | 13392.1 | 0.241058 | 0.699069 | 38.8372 | 38.8372 | 0.699069 | 80 | 0 | no | 지상 4층 | 2900 | 13401.1 | 38.8372
7561256 | 지상 4층 | 2900 | 13392.4 | 0.241062 | 0.699081 | 38.8378 | 38.8378 | 0.699081 | 80 | 0 | no | 지상 4층 | 2900 | 13401.4 | 38.8378
7561257 | 지상 4층 | 2900 | 818 | 0.014724 | 0.0426996 | 2.3722 | 2.3722 | 0.0426996 | 80 | 0 | no | 지상 4층 | 2900 | 809 | 2.3722
7561258 | 지상 4층 | 2900 | 737.5 | 0.013275 | 0.0384975 | 2.13875 | 2.13875 | 0.0384975 | 80 | 0 | no | 지상 4층 | 2900 | 737.5 | 2.13875
7561259 | 지상 4층 | 2900 | 11882 | 0.213876 | 0.62024 | 34.4578 | 34.4578 | 0.62024 | 80 | 0 | no | 지상 4층 | 2900 | 11882 | 34.4578
7561260 | 지상 4층 | 2900 | 737.5 | 0.013275 | 0.0384975 | 2.13875 | 2.13875 | 0.0384975 | 80 | 0 | no | 지상 4층 | 2900 | 737.5 | 2.13875
7561261 | 지상 4층 | 2900 | 818 | 0.014724 | 0.0426996 | 2.3722 | 2.3722 | 0.0426996 | 80 | 0 | no | 지상 4층 | 2900 | 818 | 2.3722
7561262 | 지상 4층 | 2900 | 710 | 0.01278 | 0.037062 | 2.059 | 2.059 | 0.037062 | 80 | 0 | no | 지상 4층 | 2900 | 719 | 2.059
7561263 | 지상 4층 | 2900 | 12410 | 0.22338 | 0.647802 | 35.989 | 35.989 | 0.647802 | 80 | 0 | no | 지상 4층 | 2900 | 12410 | 35.989
7561264 | 지상 4층 | 2900 | 818 | 0.014724 | 0.0426996 | 2.3722 | 2.3722 | 0.0426996 | 80 | 0 | no | 지상 4층 | 2900 | 809 | 2.3722
7561265 | 지상 4층 | 2900 | 817.983 | 0.0147237 | 0.0426987 | 2.37215 | 2.37215 | 0.0426987 | 80 | 0 | no | 지상 4층 | 2900 | 817.983 | 2.37215
7561266 | 지상 4층 | 2900 | 800 | 0.0144 | 0.04176 | 2.32 | 2.32 | 0.04176 | 80 | 0 | no | 지상 4층 | 2900 | 809 | 2.32
7561267 | 지상 4층 | 2900 | 818 | 0.014724 | 0.0426996 | 2.3722 | 2.3722 | 0.0426996 | 80 | 0 | no | 지상 4층 | 2900 | 809 | 2.3722
7561268 | 지상 4층 | 2900 | 799.983 | 0.0143997 | 0.0417591 | 2.31995 | 2.31995 | 0.0417591 | 80 | 0 | no | 지상 4층 | 2900 | 808.983 | 2.31995
7561269 | 지상 4층 | 2900 | 755.5 | 0.013599 | 0.0394371 | 2.19095 | 2.19095 | 0.0394371 | 80 | 0 | no | 지상 4층 | 2900 | 737.5 | 2.19095
7561270 | 지상 4층 | 2900 | 710.001 | 0.01278 | 0.037062 | 2.059 | 2.059 | 0.037062 | 80 | 0 | no | 지상 4층 | 2900 | 764.001 | 2.059
7561271 | 지상 4층 | 2900 | 12392 | 0.223056 | 0.646862 | 35.9368 | 35.9368 | 0.646862 | 80 | 0 | no | 지상 4층 | 2900 | 12446 | 35.9368
7561272 | 지상 4층 | 2900 | 818 | 0.014724 | 0.0426996 | 2.3722 | 2.3722 | 0.0426996 | 80 | 0 | no | 지상 4층 | 2900 | 809 | 2.3722
7561273 | 지상 4층 | 2900 | 737.483 | 0.0132747 | 0.0384966 | 2.1387 | 2.1387 | 0.0384966 | 80 | 0 | no | 지상 4층 | 2900 | 737.483 | 2.1387
7561274 | 지상 4층 | 2900 | 10864 | 0.195552 | 0.567101 | 31.5056 | 31.5056 | 0.567101 | 80 | 0 | no | 지상 4층 | 2900 | 10882 | 31.5056
7561275 | 지상 4층 | 2900 | 10882 | 0.195876 | 0.56804 | 31.5578 | 31.5578 | 0.56804 | 80 | 0 | no | 지상 4층 | 2900 | 10864 | 31.5578
7561276 | 지상 4층 | 2900 | 737.5 | 0.013275 | 0.0384975 | 2.13875 | 2.13875 | 0.0384975 | 80 | 0 | no | 지상 4층 | 2900 | 737.5 | 2.13875
7561277 | 지상 4층 | 2900 | 728 | 0.013104 | 0.0380016 | 2.1112 | 2.1112 | 0.0380016 | 80 | 0 | no | 지상 4층 | 2900 | 782 | 2.1112
7561278 | 지상 4층 | 280 | 2599.46 | 0.0467904 | 0.0131013 | 0.72785 | 0.72785 | 0.0131013 | 80 | 0 | no | 지상 4층 | 2900 | 2608.46 | 0.72785
7561279 | 지상 4층 | 2900 | 3910 | 0.07038 | 0.204102 | 11.339 | 11.339 | 0.204102 | 80 | 0 | no | 지상 4층 | 2900 | 3892 | 11.339
7561280 | 지상 4층 | 2900 | 600.009 | 0.0108002 | 0.0313205 | 1.74003 | 1.74003 | 0.0313205 | 80 | 0 | no | 지상 4층 | 2900 | 600.009 | 1.74003
7561281 | 지상 4층 | 2900 | 818 | 0.014724 | 0.0426996 | 2.3722 | 2.3722 | 0.0426996 | 80 | 0 | no | 지상 4층 | 2900 | 818 | 2.3722
7561282 | 지상 4층 | 2900 | 600.009 | 0.0108002 | 0.0313205 | 1.74003 | 1.74003 | 0.0313205 | 80 | 0 | no | 지상 4층 | 2900 | 600.009 | 1.74003
7561283 | 지상 4층 | 2900 | 8082 | 0.145476 | 0.42188 | 23.4378 | 23.4378 | 0.42188 | 80 | 0 | no | 지상 4층 | 2900 | 8082 | 23.4378
7561284 | 지상 4층 | 2900 | 599.009 | 0.0107822 | 0.0312683 | 1.73713 | 1.73713 | 0.0312683 | 80 | 0 | no | 지상 4층 | 2900 | 599.009 | 1.73713
7561285 | 지상 4층 | 2900 | 600 | 0.0108 | 0.03132 | 1.74 | 1.74 | 0.03132 | 80 | 0 | no | 지상 4층 | 2900 | 600 | 1.74
7561286 | 지상 4층 | 2900 | 9083.01 | 0.163494 | 0.474133 | 26.3407 | 22.7407 | 0.409333 | 80 | 0 | no | 지상 4층 | 2900 | 9083.01 | 22.7407
7561287 | 지상 4층 | 2900 | 600 | 0.0108 | 0.03132 | 1.74 | 1.74 | 0.03132 | 80 | 0 | no | 지상 4층 | 2900 | 600 | 1.74
7561288 | 지상 4층 | 2900 | 800 | 0.0144 | 0.04176 | 2.32 | 2.32 | 0.04176 | 80 | 0 | no | 지상 4층 | 2900 | 800 | 2.32
7561289 | 지상 4층 | 2900 | 800 | 0.0144 | 0.04176 | 2.32 | 2.32 | 0.04176 | 80 | 0 | no | 지상 4층 | 2900 | 800 | 2.32
7561290 | 지상 4층 | 2900 | 818 | 0.014724 | 0.0426996 | 2.3722 | 2.3722 | 0.0426996 | 80 | 0 | no | 지상 4층 | 2900 | 818 | 2.3722
7561291 | 지상 4층 | 2900 | 782 | 0.014076 | 0.0408204 | 2.2678 | 2.2678 | 0.0408204 | 80 | 0 | no | 지상 4층 | 2900 | 800 | 2.2678
7561292 | 지상 4층 | 2900 | 817.991 | 0.0147238 | 0.0426992 | 2.37218 | 2.37218 | 0.0426992 | 80 | 0 | no | 지상 4층 | 2900 | 808.991 | 2.37218
7561293 | 지상 4층 | 2900 | 818 | 0.014724 | 0.0426996 | 2.3722 | 2.3722 | 0.0426996 | 80 | 0 | no | 지상 4층 | 2900 | 818 | 2.3722
7561294 | 지상 4층 | 2900 | 799.983 | 0.0143997 | 0.0417591 | 2.31995 | 2.31995 | 0.0417591 | 80 | 0 | no | 지상 4층 | 2900 | 808.983 | 2.31995
7561295 | 지상 4층 | 2900 | 818 | 0.014724 | 0.0426996 | 2.3722 | 2.3722 | 0.0426996 | 80 | 0 | no | 지상 4층 | 2900 | 809 | 2.3722
7561296 | 지상 4층 | 2900 | 800 | 0.0144 | 0.04176 | 2.32 | 2.32 | 0.04176 | 80 | 0 | no | 지상 4층 | 2900 | 809 | 2.32
7561297 | 지상 4층 | 2900 | 817.999 | 0.014724 | 0.0426996 | 2.3722 | 2.3722 | 0.0426996 | 80 | 0 | no | 지상 4층 | 2900 | 883.999 | 2.3722
7561298 | 지상 4층 | 2900 | 719.5 | 0.012951 | 0.0375579 | 2.08655 | 2.08655 | 0.0375579 | 80 | 0 | no | 지상 4층 | 2900 | 737.5 | 2.08655
7561299 | 지상 4층 | 2900 | 7687.01 | 0.138366 | 0.401262 | 22.2923 | 22.2923 | 0.401262 | 80 | 0 | no | 지상 4층 | 2900 | 7687.01 | 22.2923
7562118 | 지상 5층 | 4100 | 2582.01 | 0.0464762 | 0.190552 | 10.5862 | 10.5862 | 0.190552 | 0 | 0 | no | 지상 5층 | 4100 | 2582.01 | 10.5862 | 구속조건 - 상단 구속조건: 상위 레벨: 지상 6층
7562119 | 지상 5층 | 2900 | 5482 | 0.0952064 | 0.28616 | 15.8978 | 13.5878 | 0.23598 | 0 | 0 | no | 지상 5층 | 2900 | 5482 | 13.5878
7562120 | 지상 5층 | 4100 | 2582.01 | 0.0464762 | 0.190552 | 10.5862 | 10.5862 | 0.190552 | 0 | 0 | no | 지상 5층 | 4100 | 2582.01 | 10.5862 | 구속조건 - 상단 구속조건: 상위 레벨: 지상 6층
7562121 | 지상 5층 | 4100 | 5482 | 0.098676 | 0.404572 | 22.4762 | 22.4762 | 0.404572 | 0 | 0 | no | 지상 5층 | 4100 | 5482 | 22.4762 | 구속조건 - 상단 구속조건: 상위 레벨: 지상 6층
7562122 | 지상 5층 | 4100 | 2582.01 | 0.0464762 | 0.190552 | 10.5862 | 10.5862 | 0.190552 | 0 | 0 | no | 지상 5층 | 4100 | 2582.01 | 10.5862 | 구속조건 - 상단 구속조건: 상위 레벨: 지상 6층
7562123 | 지상 5층 | 4100 | 5482 | 0.098676 | 0.404572 | 22.4762 | 22.4762 | 0.404572 | 0 | 0 | no | 지상 5층 | 4100 | 5482 | 22.4762 | 구속조건 - 상단 구속조건: 상위 레벨: 지상 6층
7562124 | 지상 5층 | 4100 | 2582.01 | 0.0464762 | 0.190552 | 10.5862 | 6.80624 | 0.122512 | 0 | 0 | no | 지상 5층 | 4100 | 2582.01 | 6.80624 | 구속조건 - 상단 구속조건: 상위 레벨: 지상 6층
7562125 | 지상 5층 | 4100 | 5482 | 0.098676 | 0.404572 | 22.4762 | 22.4762 | 0.404572 | 0 | 0 | no | 지상 5층 | 4100 | 5482 | 22.4762 | 구속조건 - 상단 구속조건: 상위 레벨: 지상 6층
7562126 | 지상 5층 | 2980 | 3282.64 | 0.0590875 | 0.176081 | 9.78227 | 9.78227 | 0.176081 | 0 | -1120 | no | 지상 5층 | 2980 | 3283.27 | 9.78227 | 구속조건 - 상단 구속조건: 상위 레벨: 지상 6층
7562127 | 지상 5층 | 2900 | 2082 | 0.037476 | 0.10868 | 6.0378 | 4.1478 | 0.0746604 | 0 | 0 | no | 지상 5층 | 2900 | 2082.02 | 4.1478
7562128 | 지상 5층 | 2980 | 3282.64 | 0.0590875 | 0.176081 | 9.78227 | 8.82227 | 0.158801 | 0 | -1120 | no | 지상 5층 | 2980 | 3282.64 | 8.82227 | 구속조건 - 상단 구속조건: 상위 레벨: 지상 6층
7562129 | 지상 5층 | 2980 | 2082 | 0.037476 | 0.111678 | 6.20436 | 3.39936 | 0.0611885 | 0 | -1120 | no | 지상 5층 | 2980 | 2082.02 | 3.39936 | 구속조건 - 상단 구속조건: 상위 레벨: 지상 6층
7562134 | 지상 5층 | 2900 | 7399.97 | 0.1332 | 0.0432 | 2.4 | 19.0599 | 0.343079 | 80 | 0 | no | 지상 5층 | 2900 | 7435.97 | 19.0599
7562135 | 지상 5층 | 2900 | 400 | 0.0072 | 0.02088 | 1.16 | 1.16 | 0.02088 | 80 | 0 | no | 지상 5층 | 2900 | 400 | 1.16
7562136 | 지상 5층 | 2900 | 400 | 0.0072 | 0.02088 | 1.16 | 1.16 | 0.02088 | 80 | 0 | no | 지상 5층 | 2900 | 400 | 1.16
7562137 | 지상 5층 | 2900 | 2082.64 | 0.0374875 | 0.108714 | 6.03966 | 6.03966 | 0.108714 | 80 | 0 | no | 지상 5층 | 2900 | 2082.64 | 6.03966
7562138 | 지상 5층 | 2900 | 599.975 | 0.0107996 | 0.0313187 | 1.73993 | 1.73993 | 0.0313187 | 80 | 0 | no | 지상 5층 | 2900 | 599.975 | 1.73993
7562139 | 지상 5층 | 2900 | 817.35 | 0.0147123 | 0.0426657 | 2.37031 | 2.37031 | 0.0426657 | 80 | 0 | no | 지상 5층 | 2900 | 817.35 | 2.37031
7562140 | 지상 5층 | 2900 | 599.975 | 0.0107996 | 0.0313187 | 1.73993 | 1.73993 | 0.0313187 | 80 | 0 | no | 지상 5층 | 2900 | 599.975 | 1.73993
7562141 | 지상 5층 | 2900 | 11864.6 | 0.213563 | 0.619334 | 34.4074 | 30.8074 | 0.554534 | 80 | 0 | no | 지상 5층 | 2900 | 11882.6 | 30.8074
7562142 | 지상 5층 | 2900 | 18 | 0.000324 | 0.0009396 | 0.0522 | 0.0522 | 0.0009396 | 80 | 0 | no | 지상 5층 | 2900 | 9 | 0.0522
7562143 | 지상 5층 | 2900 | 818.615 | 0.0147351 | 0.0427317 | 2.37398 | 2.37398 | 0.0427317 | 80 | 0 | no | 지상 5층 | 2900 | 800.615 | 2.37398
7562144 | 지상 5층 | 2900 | 13500.6 | 0.243011 | 0.704733 | 39.1518 | 39.1518 | 0.704733 | 80 | 0 | no | 지상 5층 | 2900 | 13500.6 | 39.1518
7562145 | 지상 5층 | 2900 | 728.367 | 0.0131106 | 0.0380208 | 2.11226 | 2.11226 | 0.0380208 | 80 | 0 | no | 지상 5층 | 2900 | 719.367 | 2.11226
7562146 | 지상 5층 | 2900 | 737.499 | 0.013275 | 0.0384975 | 2.13875 | 2.13875 | 0.0384975 | 80 | 0 | no | 지상 5층 | 2900 | 737.499 | 2.13875
7562147 | 지상 5층 | 2900 | 11882 | 0.213876 | 0.62024 | 34.4578 | 34.4578 | 0.62024 | 80 | 0 | no | 지상 5층 | 2900 | 11882 | 34.4578
7562148 | 지상 5층 | 2900 | 737.499 | 0.013275 | 0.0384975 | 2.13875 | 2.13875 | 0.0384975 | 80 | 0 | no | 지상 5층 | 2900 | 737.499 | 2.13875
7562149 | 지상 5층 | 2900 | 782.633 | 0.0140874 | 0.0408534 | 2.26964 | 2.26964 | 0.0408534 | 80 | 0 | no | 지상 5층 | 2900 | 800.633 | 2.26964
7562153 | 지상 5층 | 2900 | 809.035 | 0.0145626 | 0.0422316 | 2.3462 | 2.3462 | 0.0422316 | 80 | 0 | no | 지상 5층 | 2900 | 800.035 | 2.3462
7562154 | 지상 5층 | 2900 | 711 | 0.012798 | 0.0371142 | 2.0619 | 2.0619 | 0.0371142 | 80 | 0 | no | 지상 5층 | 2900 | 720 | 2.0619
7562155 | 지상 5층 | 2900 | 13392.6 | 0.241067 | 0.699095 | 38.8386 | 38.8386 | 0.699095 | 80 | 0 | no | 지상 5층 | 2900 | 13401.6 | 38.8386
7562156 | 지상 5층 | 2900 | 13392.7 | 0.241068 | 0.699097 | 38.8387 | 38.8387 | 0.699097 | 80 | 0 | no | 지상 5층 | 2900 | 13401.7 | 38.8387
7562157 | 지상 5층 | 2900 | 818.633 | 0.0147354 | 0.0427326 | 2.37404 | 2.37404 | 0.0427326 | 80 | 0 | no | 지상 5층 | 2900 | 809.633 | 2.37404
7562158 | 지상 5층 | 2900 | 737.491 | 0.0132748 | 0.038497 | 2.13872 | 2.13872 | 0.038497 | 80 | 0 | no | 지상 5층 | 2900 | 737.491 | 2.13872
7562159 | 지상 5층 | 2900 | 11882 | 0.213876 | 0.620239 | 34.4577 | 34.4577 | 0.620239 | 80 | 0 | no | 지상 5층 | 2900 | 11882 | 34.4577
7562160 | 지상 5층 | 2900 | 737.491 | 0.0132748 | 0.038497 | 2.13872 | 2.13872 | 0.038497 | 80 | 0 | no | 지상 5층 | 2900 | 737.491 | 2.13872
7562161 | 지상 5층 | 2900 | 817.384 | 0.0147129 | 0.0426675 | 2.37041 | 2.37041 | 0.0426675 | 80 | 0 | no | 지상 5층 | 2900 | 817.384 | 2.37041
7562162 | 지상 5층 | 2900 | 711 | 0.012798 | 0.0371142 | 2.0619 | 2.0619 | 0.0371142 | 80 | 0 | no | 지상 5층 | 2900 | 720 | 2.0619
7562163 | 지상 5층 | 2900 | 12410 | 0.22338 | 0.647802 | 35.989 | 35.989 | 0.647802 | 80 | 0 | no | 지상 5층 | 2900 | 12410 | 35.989
7562164 | 지상 5층 | 2900 | 818 | 0.014724 | 0.0426996 | 2.3722 | 2.3722 | 0.0426996 | 80 | 0 | no | 지상 5층 | 2900 | 809 | 2.3722
7562165 | 지상 5층 | 2900 | 818 | 0.014724 | 0.0426996 | 2.3722 | 2.3722 | 0.0426996 | 80 | 0 | no | 지상 5층 | 2900 | 818 | 2.3722
7562166 | 지상 5층 | 2900 | 800 | 0.0144 | 0.04176 | 2.32 | 2.32 | 0.04176 | 80 | 0 | no | 지상 5층 | 2900 | 809 | 2.32
7562167 | 지상 5층 | 2900 | 818.025 | 0.0147245 | 0.0427009 | 2.37227 | 2.37227 | 0.0427009 | 80 | 0 | no | 지상 5층 | 2900 | 809.025 | 2.37227
7562168 | 지상 5층 | 2900 | 800.633 | 0.0144114 | 0.041793 | 2.32184 | 2.32184 | 0.041793 | 80 | 0 | no | 지상 5층 | 2900 | 809.633 | 2.32184
7562169 | 지상 5층 | 2900 | 755.5 | 0.013599 | 0.0394371 | 2.19095 | 2.19095 | 0.0394371 | 80 | 0 | no | 지상 5층 | 2900 | 737.5 | 2.19095
7562170 | 지상 5층 | 2900 | 711 | 0.012798 | 0.0371142 | 2.0619 | 2.0619 | 0.0371142 | 80 | 0 | no | 지상 5층 | 2900 | 720 | 2.0619
7562171 | 지상 5층 | 2900 | 12392 | 0.223056 | 0.646862 | 35.9368 | 35.9368 | 0.646862 | 80 | 0 | no | 지상 5층 | 2900 | 12446 | 35.9368
7562172 | 지상 5층 | 2900 | 818 | 0.014724 | 0.0426996 | 2.3722 | 2.3722 | 0.0426996 | 80 | 0 | no | 지상 5층 | 2900 | 809 | 2.3722
7562173 | 지상 5층 | 2900 | 737.517 | 0.0132753 | 0.0384984 | 2.1388 | 2.1388 | 0.0384984 | 80 | 0 | no | 지상 5층 | 2900 | 737.517 | 2.1388
7562174 | 지상 5층 | 2900 | 10864 | 0.195552 | 0.567101 | 31.5056 | 31.5056 | 0.567101 | 80 | 0 | no | 지상 5층 | 2900 | 10882 | 31.5056
7562175 | 지상 5층 | 2900 | 10900 | 0.1962 | 0.56898 | 31.61 | 31.61 | 0.56898 | 80 | 0 | no | 지상 5층 | 2900 | 10882 | 31.61
7562176 | 지상 5층 | 2900 | 737.535 | 0.0132756 | 0.0384993 | 2.13885 | 2.13885 | 0.0384993 | 80 | 0 | no | 지상 5층 | 2900 | 737.535 | 2.13885
7562177 | 지상 5층 | 2900 | 655.025 | 0.0117905 | 0.0341923 | 1.89957 | 1.89957 | 0.0341923 | 80 | 0 | no | 지상 5층 | 2900 | 664.025 | 1.89957
7562178 | 지상 5층 | 280 | 2609.4 | 0.0469693 | 0.0131514 | 0.730633 | 0.730633 | 0.0131514 | 80 | 0 | no | 지상 5층 | 2900 | 2618.4 | 0.730633
7562179 | 지상 5층 | 2900 | 3887.03 | 0.0699666 | 0.202903 | 11.2724 | 11.2724 | 0.202903 | 80 | 0 | no | 지상 5층 | 2900 | 3887.03 | 11.2724
7562180 | 지상 5층 | 2900 | 499.642 | 0.00899355 | 0.0260813 | 1.44896 | 1.44896 | 0.0260813 | 80 | 0 | no | 지상 5층 | 2900 | 499.642 | 1.44896
7562181 | 지상 5층 | 2900 | 718.025 | 0.0129245 | 0.0374809 | 2.08227 | 2.08227 | 0.0374809 | 80 | 0 | no | 지상 5층 | 2900 | 718.025 | 2.08227
7562182 | 지상 5층 | 2900 | 499.009 | 0.00898216 | 0.0260483 | 1.44713 | 1.44713 | 0.0260483 | 80 | 0 | no | 지상 5층 | 2900 | 499.009 | 1.44713
7562183 | 지상 5층 | 2900 | 8282 | 0.149076 | 0.43232 | 24.0178 | 24.0178 | 0.43232 | 80 | 0 | no | 지상 5층 | 2900 | 8282 | 24.0178
7562184 | 지상 5층 | 2900 | 499.991 | 0.00899984 | 0.0260995 | 1.44997 | 1.44997 | 0.0260995 | 80 | 0 | no | 지상 5층 | 2900 | 499.991 | 1.44997
7562185 | 지상 5층 | 2900 | 500 | 0.009 | 0.0261 | 1.45 | 1.45 | 0.0261 | 80 | 0 | no | 지상 5층 | 2900 | 500 | 1.45
7562186 | 지상 5층 | 2900 | 9282.01 | 0.167076 | 0.484521 | 26.9178 | 23.3178 | 0.419721 | 0 | 0 | no | 지상 5층 | 2900 | 9282.01 | 23.3178
7562187 | 지상 5층 | 2900 | 500 | 0.009 | 0.0261 | 1.45 | 1.45 | 0.0261 | 80 | 0 | no | 지상 5층 | 2900 | 500 | 1.45
7562188 | 지상 5층 | 2900 | 700 | 0.0126 | 0.03654 | 2.03 | 2.03 | 0.03654 | 80 | 0 | no | 지상 5층 | 2900 | 700 | 2.03
7562189 | 지상 5층 | 2900 | 699.983 | 0.0125997 | 0.0365391 | 2.02995 | 2.02995 | 0.0365391 | 80 | 0 | no | 지상 5층 | 2900 | 699.983 | 2.02995
7562190 | 지상 5층 | 2900 | 718.025 | 0.0129245 | 0.0374809 | 2.08227 | 2.08227 | 0.0374809 | 80 | 0 | no | 지상 5층 | 2900 | 718.025 | 2.08227
7562191 | 지상 5층 | 2900 | 681.983 | 0.0122757 | 0.0355995 | 1.97775 | 1.97775 | 0.0355995 | 80 | 0 | no | 지상 5층 | 2900 | 699.983 | 1.97775
7562192 | 지상 5층 | 2900 | 817.991 | 0.0147238 | 0.0426992 | 2.37218 | 2.37218 | 0.0426992 | 80 | 0 | no | 지상 5층 | 2900 | 808.991 | 2.37218
7562193 | 지상 5층 | 2900 | 818 | 0.014724 | 0.0426996 | 2.3722 | 2.3722 | 0.0426996 | 80 | 0 | no | 지상 5층 | 2900 | 818 | 2.3722
7562194 | 지상 5층 | 2900 | 799.983 | 0.0143997 | 0.0417591 | 2.31995 | 2.31995 | 0.0417591 | 80 | 0 | no | 지상 5층 | 2900 | 808.983 | 2.31995
7562195 | 지상 5층 | 2900 | 817.991 | 0.0147238 | 0.0426991 | 2.37217 | 2.37217 | 0.0426991 | 80 | 0 | no | 지상 5층 | 2900 | 808.991 | 2.37217
7562196 | 지상 5층 | 2900 | 800 | 0.0144 | 0.04176 | 2.32 | 2.32 | 0.04176 | 80 | 0 | no | 지상 5층 | 2900 | 809 | 2.32
7562197 | 지상 5층 | 2900 | 817.974 | 0.0147235 | 0.0426983 | 2.37213 | 2.37213 | 0.0426983 | 80 | 0 | no | 지상 5층 | 2900 | 883.974 | 2.37213
7562198 | 지상 5층 | 2900 | 719.517 | 0.0129513 | 0.0375588 | 2.0866 | 2.0866 | 0.0375588 | 80 | 0 | no | 지상 5층 | 2900 | 737.517 | 2.0866
7562199 | 지상 5층 | 2900 | 7686.99 | 0.138366 | 0.401261 | 22.2923 | 22.2923 | 0.401261 | 80 | 0 | no | 지상 5층 | 2900 | 7740.99 | 22.2923
7563416 | 지상 6층 | 4100 | 2582.01 | 0.0464762 | 0.190552 | 10.5862 | 10.5862 | 0.190552 | 0 | 0 | no | 지상 6층 | 4100 | 2582.01 | 10.5862 | 구속조건 - 상단 구속조건: 상위 레벨: 지상 7층
7563417 | 지상 6층 | 2900 | 5482 | 0.098676 | 0.28616 | 15.8978 | 13.5878 | 0.24458 | 0 | 0 | no | 지상 6층 | 2900 | 5482 | 13.5878
7563418 | 지상 6층 | 4100 | 2582.01 | 0.0464762 | 0.190552 | 10.5862 | 10.5862 | 0.190552 | 0 | 0 | no | 지상 6층 | 4100 | 2582.01 | 10.5862 | 구속조건 - 상단 구속조건: 상위 레벨: 지상 7층
7563419 | 지상 6층 | 4100 | 5482 | 0.098676 | 0.404572 | 22.4762 | 22.4762 | 0.404572 | 0 | 0 | no | 지상 6층 | 4100 | 5482 | 22.4762 | 구속조건 - 상단 구속조건: 상위 레벨: 지상 7층
7563420 | 지상 6층 | 4100 | 2582.63 | 0.0464874 | 0.190598 | 10.5888 | 10.5888 | 0.190598 | 0 | 0 | no | 지상 6층 | 4100 | 2582.63 | 10.5888 | 구속조건 - 상단 구속조건: 상위 레벨: 지상 7층
7563421 | 지상 6층 | 4100 | 5482.03 | 0.0952068 | 0.404573 | 22.4763 | 22.4763 | 0.390348 | 0 | 0 | no | 지상 6층 | 4100 | 5482.03 | 22.4763 | 구속조건 - 상단 구속조건: 상위 레벨: 지상 7층
7563422 | 지상 6층 | 4100 | 2582.63 | 0.0464874 | 0.190598 | 10.5888 | 6.80879 | 0.122558 | 0 | 0 | no | 지상 6층 | 4100 | 2582.63 | 6.80879 | 구속조건 - 상단 구속조건: 상위 레벨: 지상 7층
7563423 | 지상 6층 | 4100 | 5482.03 | 0.0986765 | 0.404573 | 22.4763 | 22.4763 | 0.404573 | 0 | 0 | no | 지상 6층 | 4100 | 5482.03 | 22.4763 | 구속조건 - 상단 구속조건: 상위 레벨: 지상 7층
7563424 | 지상 6층 | 4100 | 3282.01 | 0.0590762 | 0.242212 | 13.4562 | 13.4562 | 0.242212 | 0 | 0 | no | 지상 6층 | 4100 | 3282.01 | 13.4562 | 구속조건 - 상단 구속조건: 상위 레벨: 지상 7층
7563425 | 지상 6층 | 2900 | 2082 | 0.037476 | 0.10868 | 6.0378 | 4.1478 | 0.0746604 | 0 | 0 | no | 지상 6층 | 2900 | 2082 | 4.1478
7563426 | 지상 6층 | 4100 | 3282.01 | 0.0590762 | 0.242212 | 13.4562 | 12.4962 | 0.224932 | 0 | 0 | no | 지상 6층 | 4100 | 3282.01 | 12.4962 | 구속조건 - 상단 구속조건: 상위 레벨: 지상 7층
7563427 | 지상 6층 | 4100 | 2082 | 0.037476 | 0.153652 | 8.5362 | 5.7312 | 0.103162 | 0 | 0 | no | 지상 6층 | 4100 | 2082 | 5.7312 | 구속조건 - 상단 구속조건: 상위 레벨: 지상 7층
7563432 | 지상 6층 | 2900 | 7400 | 0.1332 | 0.0432 | 2.4 | 19.06 | 0.34308 | 80 | 0 | no | 지상 6층 | 2900 | 7436 | 19.06
7563433 | 지상 6층 | 2900 | 400.017 | 0.00720031 | 0.0208809 | 1.16005 | 1.16005 | 0.0208809 | 80 | 0 | no | 지상 6층 | 2900 | 400.017 | 1.16005
7563434 | 지상 6층 | 2900 | 399.974 | 0.00719954 | 0.0208787 | 1.15993 | 1.15993 | 0.0208787 | 80 | 0 | no | 지상 6층 | 2900 | 399.974 | 1.15993
7563435 | 지상 6층 | 2900 | 2082.61 | 0.0374869 | 0.108712 | 6.03956 | 6.03956 | 0.108712 | 80 | 0 | no | 지상 6층 | 2900 | 2082.61 | 6.03956
7563436 | 지상 6층 | 2900 | 600 | 0.0108 | 0.03132 | 1.74 | 1.74 | 0.03132 | 80 | 0 | no | 지상 6층 | 2900 | 600 | 1.74
7563437 | 지상 6층 | 2900 | 817.384 | 0.0147129 | 0.0426675 | 2.37041 | 2.37041 | 0.0426675 | 80 | 0 | no | 지상 6층 | 2900 | 817.384 | 2.37041
7563438 | 지상 6층 | 2900 | 600.025 | 0.0108005 | 0.0313213 | 1.74007 | 1.74007 | 0.0313213 | 80 | 0 | no | 지상 6층 | 2900 | 600.025 | 1.74007
7563439 | 지상 6층 | 2900 | 11864 | 0.213552 | 0.619301 | 34.4056 | 30.8056 | 0.554501 | 80 | 0 | no | 지상 6층 | 2900 | 11873 | 30.8056
7563440 | 지상 6층 | 2900 | 8.97461 | 0.000161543 | 0.0009396 | 0.0522 | 0.0522 | 0.000468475 | 80 | 0 | no | 지상 6층 | 2900 | 8.97461 | 0.0260264
7563441 | 지상 6층 | 2900 | 818 | 0.014724 | 0.0426996 | 2.3722 | 2.3722 | 0.0426996 | 80 | 0 | no | 지상 6층 | 2900 | 800 | 2.3722
7563442 | 지상 6층 | 2900 | 13500.6 | 0.243011 | 0.704732 | 39.1518 | 39.1518 | 0.704732 | 80 | 0 | no | 지상 6층 | 2900 | 13500.6 | 39.1518
7563443 | 지상 6층 | 2900 | 727.983 | 0.0131037 | 0.0380007 | 2.11115 | 2.11115 | 0.0380007 | 80 | 0 | no | 지상 6층 | 2900 | 718.983 | 2.11115
7563444 | 지상 6층 | 2900 | 737.5 | 0.013275 | 0.0384975 | 2.13875 | 2.13875 | 0.0384975 | 80 | 0 | no | 지상 6층 | 2900 | 737.5 | 2.13875
7563445 | 지상 6층 | 2900 | 11882.6 | 0.213887 | 0.620273 | 34.4596 | 34.4596 | 0.620273 | 80 | 0 | no | 지상 6층 | 2900 | 11882.6 | 34.4596
7563446 | 지상 6층 | 2900 | 737.5 | 0.013275 | 0.0384975 | 2.13875 | 2.13875 | 0.0384975 | 80 | 0 | no | 지상 6층 | 2900 | 737.5 | 2.13875
7563447 | 지상 6층 | 2900 | 791.05 | 0.0142389 | 0.0412928 | 2.29404 | 2.29404 | 0.0412928 | 80 | 0 | no | 지상 6층 | 2900 | 800.05 | 2.29404
7563451 | 지상 6층 | 2900 | 809.035 | 0.0145626 | 0.0422316 | 2.3462 | 2.3462 | 0.0422316 | 80 | 0 | no | 지상 6층 | 2900 | 800.035 | 2.3462
7563452 | 지상 6층 | 2900 | 711 | 0.012798 | 0.0371142 | 2.0619 | 2.0619 | 0.0371142 | 80 | 0 | no | 지상 6층 | 2900 | 720 | 2.0619
7563453 | 지상 6층 | 2900 | 13392 | 0.241056 | 0.699062 | 38.8368 | 38.8368 | 0.699062 | 80 | 0 | no | 지상 6층 | 2900 | 13401 | 38.8368
7563454 | 지상 6층 | 2900 | 13392 | 0.241056 | 0.699064 | 38.8369 | 38.8369 | 0.699064 | 80 | 0 | no | 지상 6층 | 2900 | 13401 | 38.8369
7563455 | 지상 6층 | 2900 | 818.633 | 0.0147354 | 0.0427326 | 2.37404 | 2.37404 | 0.0427326 | 80 | 0 | no | 지상 6층 | 2900 | 809.633 | 2.37404
7563456 | 지상 6층 | 2900 | 737.525 | 0.0132754 | 0.0384988 | 2.13882 | 2.13882 | 0.0384988 | 80 | 0 | no | 지상 6층 | 2900 | 737.525 | 2.13882
7563457 | 지상 6층 | 2900 | 11882 | 0.213876 | 0.620239 | 34.4577 | 34.4577 | 0.620239 | 80 | 0 | no | 지상 6층 | 2900 | 11882 | 34.4577
7563458 | 지상 6층 | 2900 | 737.525 | 0.0132754 | 0.0384988 | 2.13882 | 2.13882 | 0.0384988 | 80 | 0 | no | 지상 6층 | 2900 | 737.525 | 2.13882
7563459 | 지상 6층 | 2900 | 817.965 | 0.0147234 | 0.0426978 | 2.3721 | 2.3721 | 0.0426978 | 80 | 0 | no | 지상 6층 | 2900 | 817.965 | 2.3721
7563460 | 지상 6층 | 2900 | 710.041 | 0.0127807 | 0.0370641 | 2.05912 | 2.05912 | 0.0370641 | 80 | 0 | no | 지상 6층 | 2900 | 719.041 | 2.05912
7563461 | 지상 6층 | 2900 | 12410.6 | 0.223391 | 0.647835 | 35.9908 | 35.9908 | 0.647835 | 80 | 0 | no | 지상 6층 | 2900 | 12410.6 | 35.9908
7563462 | 지상 6층 | 2900 | 818 | 0.014724 | 0.0426996 | 2.3722 | 2.3722 | 0.0426996 | 80 | 0 | no | 지상 6층 | 2900 | 809 | 2.3722
7563463 | 지상 6층 | 2900 | 817.983 | 0.0147237 | 0.0426987 | 2.37215 | 2.37215 | 0.0426987 | 80 | 0 | no | 지상 6층 | 2900 | 817.983 | 2.37215
7563464 | 지상 6층 | 2900 | 800 | 0.0144 | 0.04176 | 2.32 | 2.32 | 0.04176 | 80 | 0 | no | 지상 6층 | 2900 | 809 | 2.32
7563465 | 지상 6층 | 2900 | 818.025 | 0.0147244 | 0.0427009 | 2.37227 | 2.37227 | 0.0427009 | 80 | 0 | no | 지상 6층 | 2900 | 809.025 | 2.37227
7563466 | 지상 6층 | 2900 | 800.044 | 0.0144008 | 0.0417623 | 2.32013 | 2.32013 | 0.0417623 | 80 | 0 | no | 지상 6층 | 2900 | 809.044 | 2.32013
7563467 | 지상 6층 | 2900 | 755.483 | 0.0135987 | 0.0394362 | 2.1909 | 2.1909 | 0.0394362 | 80 | 0 | no | 지상 6층 | 2900 | 737.483 | 2.1909
7563468 | 지상 6층 | 2900 | 710.026 | 0.0127805 | 0.0370633 | 2.05907 | 2.05907 | 0.0370633 | 80 | 0 | no | 지상 6층 | 2900 | 764.026 | 2.05907
7563469 | 지상 6층 | 2900 | 12392 | 0.223056 | 0.646862 | 35.9368 | 35.9368 | 0.646862 | 80 | 0 | no | 지상 6층 | 2900 | 12446 | 35.9368
7563470 | 지상 6층 | 2900 | 817.986 | 0.0147238 | 0.0426989 | 2.37216 | 2.37216 | 0.0426989 | 80 | 0 | no | 지상 6층 | 2900 | 808.986 | 2.37216
7563471 | 지상 6층 | 2900 | 737.483 | 0.0132747 | 0.0384966 | 2.1387 | 2.1387 | 0.0384966 | 80 | 0 | no | 지상 6층 | 2900 | 737.483 | 2.1387
7563472 | 지상 6층 | 2900 | 10864 | 0.195552 | 0.567099 | 31.5055 | 31.5055 | 0.567099 | 80 | 0 | no | 지상 6층 | 2900 | 10882 | 31.5055
7563473 | 지상 6층 | 2900 | 10900 | 0.1962 | 0.56898 | 31.61 | 31.61 | 0.56898 | 80 | 0 | no | 지상 6층 | 2900 | 10882 | 31.61
7563474 | 지상 6층 | 2900 | 737.5 | 0.013275 | 0.0384975 | 2.13875 | 2.13875 | 0.0384975 | 80 | 0 | no | 지상 6층 | 2900 | 737.5 | 2.13875
7563475 | 지상 6층 | 2900 | 710.026 | 0.0127805 | 0.0370633 | 2.05907 | 2.05907 | 0.0370633 | 80 | 0 | no | 지상 6층 | 2900 | 764.026 | 2.05907
7563477 | 지상 6층 | 2900 | 3909.99 | 0.0703799 | 0.204102 | 11.339 | 11.339 | 0.204102 | 80 | 0 | no | 지상 6층 | 2900 | 3891.99 | 11.339
7563478 | 지상 6층 | 2900 | 500.009 | 0.00900016 | 0.0261005 | 1.45003 | 1.45003 | 0.0261005 | 80 | 0 | no | 지상 6층 | 2900 | 500.009 | 1.45003
7563479 | 지상 6층 | 2900 | 718.025 | 0.0129245 | 0.0374809 | 2.08227 | 2.08227 | 0.0374809 | 80 | 0 | no | 지상 6층 | 2900 | 718.025 | 2.08227
7563480 | 지상 6층 | 2900 | 500.009 | 0.00900016 | 0.0261005 | 1.45003 | 1.45003 | 0.0261005 | 80 | 0 | no | 지상 6층 | 2900 | 500.009 | 1.45003
7563481 | 지상 6층 | 2900 | 8282 | 0.149076 | 0.43232 | 24.0178 | 24.0178 | 0.43232 | 80 | 0 | no | 지상 6층 | 2900 | 8282 | 24.0178
7563482 | 지상 6층 | 2900 | 499.991 | 0.00899984 | 0.0260995 | 1.44997 | 1.44997 | 0.0260995 | 80 | 0 | no | 지상 6층 | 2900 | 499.991 | 1.44997
7563483 | 지상 6층 | 2900 | 482 | 0.00867601 | 0.0251604 | 1.3978 | 1.3978 | 0.0251604 | 80 | 0 | no | 지상 6층 | 2900 | 500 | 1.3978
7563484 | 지상 6층 | 2900 | 9300.01 | 0.1674 | 0.48546 | 26.97 | 23.37 | 0.42066 | 0 | 0 | no | 지상 6층 | 2900 | 9282.01 | 23.37
7563485 | 지상 6층 | 2900 | 500 | 0.009 | 0.0261 | 1.45 | 1.45 | 0.0261 | 80 | 0 | no | 지상 6층 | 2900 | 500 | 1.45
7563486 | 지상 6층 | 2900 | 700 | 0.0126 | 0.03654 | 2.03 | 2.03 | 0.03654 | 80 | 0 | no | 지상 6층 | 2900 | 700 | 2.03
7563487 | 지상 6층 | 2900 | 699.983 | 0.0125997 | 0.0365391 | 2.02995 | 2.02995 | 0.0365391 | 80 | 0 | no | 지상 6층 | 2900 | 699.983 | 2.02995
7563488 | 지상 6층 | 2900 | 718.025 | 0.0129245 | 0.0374809 | 2.08227 | 2.08227 | 0.0374809 | 80 | 0 | no | 지상 6층 | 2900 | 718.025 | 2.08227
7563489 | 지상 6층 | 2900 | 681.983 | 0.0122757 | 0.0355995 | 1.97775 | 1.97775 | 0.0355995 | 80 | 0 | no | 지상 6층 | 2900 | 699.983 | 1.97775
7563490 | 지상 6층 | 2900 | 817.358 | 0.0147125 | 0.0426661 | 2.37034 | 2.37034 | 0.0426661 | 80 | 0 | no | 지상 6층 | 2900 | 808.358 | 2.37034
7563491 | 지상 6층 | 2900 | 817.974 | 0.0147235 | 0.0426983 | 2.37213 | 2.37213 | 0.0426983 | 80 | 0 | no | 지상 6층 | 2900 | 817.974 | 2.37213
7563492 | 지상 6층 | 2900 | 799.35 | 0.0143883 | 0.0417261 | 2.31811 | 2.31811 | 0.0417261 | 80 | 0 | no | 지상 6층 | 2900 | 808.35 | 2.31811
7563493 | 지상 6층 | 2900 | 817.367 | 0.0147126 | 0.0426666 | 2.37036 | 2.37036 | 0.0426666 | 80 | 0 | no | 지상 6층 | 2900 | 808.367 | 2.37036
7563494 | 지상 6층 | 2900 | 800.025 | 0.0144004 | 0.0417613 | 2.32007 | 2.32007 | 0.0417613 | 80 | 0 | no | 지상 6층 | 2900 | 809.025 | 2.32007
7563495 | 지상 6층 | 2900 | 817.974 | 0.0147235 | 0.0426983 | 2.37213 | 2.37213 | 0.0426983 | 80 | 0 | no | 지상 6층 | 2900 | 883.974 | 2.37213
7563496 | 지상 6층 | 2900 | 719.5 | 0.012951 | 0.0375579 | 2.08655 | 2.08655 | 0.0375579 | 80 | 0 | no | 지상 6층 | 2900 | 737.5 | 2.08655
7563497 | 지상 6층 | 2900 | 7686.99 | 0.138366 | 0.401261 | 22.2923 | 22.2923 | 0.401261 | 80 | 0 | no | 지상 6층 | 2900 | 7740.99 | 22.2923
7563500 | 지상 7층 | 4100 | 2582.01 | 0.0464762 | 0.190552 | 10.5862 | 10.5862 | 0.190552 | 0 | 0 | no | 지상 7층 | 4100 | 2582.01 | 10.5862 | 구속조건 - 상단 구속조건: 상위 레벨: 지상 8층
7563501 | 지상 7층 | 2900 | 5482 | 0.098676 | 0.28616 | 15.8978 | 15.8978 | 0.28616 | 0 | 0 | no | 지상 7층 | 2900 | 5482 | 15.8978
7563502 | 지상 7층 | 4100 | 2582.01 | 0.0464762 | 0.190552 | 10.5862 | 10.5862 | 0.190552 | 0 | 0 | no | 지상 7층 | 4100 | 2582.01 | 10.5862 | 구속조건 - 상단 구속조건: 상위 레벨: 지상 8층
7563503 | 지상 7층 | 4100 | 5482 | 0.098676 | 0.404572 | 22.4762 | 22.4762 | 0.404572 | 0 | 0 | no | 지상 7층 | 4100 | 5482 | 22.4762 | 구속조건 - 상단 구속조건: 상위 레벨: 지상 8층
7563504 | 지상 7층 | 4100 | 2582.01 | 0.0464762 | 0.190552 | 10.5862 | 10.5862 | 0.190552 | 0 | 0 | no | 지상 7층 | 4100 | 2582.01 | 10.5862 | 구속조건 - 상단 구속조건: 상위 레벨: 지상 8층
7563505 | 지상 7층 | 4100 | 5482 | 0.098676 | 0.404572 | 22.4762 | 22.4762 | 0.404572 | 0 | 0 | no | 지상 7층 | 4100 | 5482 | 22.4762 | 구속조건 - 상단 구속조건: 상위 레벨: 지상 8층
7563506 | 지상 7층 | 4100 | 2582.01 | 0.0464762 | 0.190552 | 10.5862 | 6.80624 | 0.122512 | 0 | 0 | no | 지상 7층 | 4100 | 2582.01 | 6.80624 | 구속조건 - 상단 구속조건: 상위 레벨: 지상 8층
7563507 | 지상 7층 | 4100 | 5482 | 0.098676 | 0.404572 | 22.4762 | 22.4762 | 0.404572 | 0 | 0 | no | 지상 7층 | 4100 | 5482 | 22.4762 | 구속조건 - 상단 구속조건: 상위 레벨: 지상 8층
7563508 | 지상 7층 | 2900 | 3282.01 | 0.0590762 | 0.171321 | 9.51783 | 9.51783 | 0.171321 | 0 | 0 | no | 지상 7층 | 2900 | 3282.01 | 9.51783
7563509 | 지상 7층 | 2900 | 2082 | 0.0361583 | 0.10868 | 6.0378 | 4.1478 | 0.0720352 | 0 | 0 | no | 지상 7층 | 2900 | 2082 | 4.1478
7563510 | 지상 7층 | 2900 | 3282.01 | 0.0590762 | 0.171321 | 9.51783 | 8.55783 | 0.154041 | 0 | 0 | no | 지상 7층 | 2900 | 3282.01 | 8.55783
7563511 | 지상 7층 | 2900 | 2082 | 0.037476 | 0.10868 | 6.0378 | 3.2328 | 0.0581904 | 0 | 0 | no | 지상 7층 | 2900 | 2082 | 3.2328
7563516 | 지상 7층 | 2900 | 7400 | 0.1332 | 0.0432 | 2.4 | 19.06 | 0.34308 | 80 | 0 | no | 지상 7층 | 2900 | 7436 | 19.06
7563517 | 지상 7층 | 2900 | 400 | 0.0072 | 0.02088 | 1.16 | 1.16 | 0.02088 | 80 | 0 | no | 지상 7층 | 2900 | 400 | 1.16
7563518 | 지상 7층 | 2900 | 400 | 0.00719999 | 0.02088 | 1.16 | 1.16 | 0.02088 | 80 | 0 | no | 지상 7층 | 2900 | 400 | 1.16
7563519 | 지상 7층 | 2900 | 2081.99 | 0.0374758 | 0.10868 | 6.03777 | 6.03777 | 0.10868 | 80 | 0 | no | 지상 7층 | 2900 | 2081.99 | 6.03777
7563520 | 지상 7층 | 2900 | 600 | 0.0108 | 0.03132 | 1.74 | 1.74 | 0.03132 | 80 | 0 | no | 지상 7층 | 2900 | 600 | 1.74
7563521 | 지상 7층 | 2900 | 818 | 0.014724 | 0.0426996 | 2.3722 | 2.3722 | 0.0426996 | 80 | 0 | no | 지상 7층 | 2900 | 818 | 2.3722
7563522 | 지상 7층 | 2900 | 600 | 0.0108 | 0.03132 | 1.74 | 1.74 | 0.03132 | 80 | 0 | no | 지상 7층 | 2900 | 600 | 1.74
7563523 | 지상 7층 | 2900 | 11864.6 | 0.213563 | 0.619334 | 34.4074 | 30.8074 | 0.554534 | 80 | 0 | no | 지상 7층 | 2900 | 11882.6 | 30.8074
7563524 | 지상 7층 | 2900 | 17.9746 | 0.000323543 | 0.0009396 | 0.0522 | 0.0522 | 0.000938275 | 80 | 0 | no | 지상 7층 | 2900 | 8.97461 | 0.0521264
7563525 | 지상 7층 | 2900 | 818.017 | 0.0147243 | 0.0427005 | 2.37225 | 2.37225 | 0.0427005 | 80 | 0 | no | 지상 7층 | 2900 | 800.017 | 2.37225
7563526 | 지상 7층 | 2900 | 13500.6 | 0.243011 | 0.704732 | 39.1518 | 39.1518 | 0.704732 | 80 | 0 | no | 지상 7층 | 2900 | 13500.6 | 39.1518
7563527 | 지상 7층 | 2900 | 673.616 | 0.0121251 | 0.0351627 | 1.95349 | 1.95349 | 0.0351627 | 80 | 0 | no | 지상 7층 | 2900 | 664.616 | 1.95349
7563528 | 지상 7층 | 2900 | 737.5 | 0.013275 | 0.0384975 | 2.13875 | 2.13875 | 0.0384975 | 80 | 0 | no | 지상 7층 | 2900 | 737.5 | 2.13875
7563529 | 지상 7층 | 2900 | 11882 | 0.213876 | 0.62024 | 34.4578 | 34.4578 | 0.62024 | 80 | 0 | no | 지상 7층 | 2900 | 11882 | 34.4578
7563530 | 지상 7층 | 2900 | 737.475 | 0.0132746 | 0.0384962 | 2.13868 | 2.13868 | 0.0384962 | 80 | 0 | no | 지상 7층 | 2900 | 737.475 | 2.13868
7563531 | 지상 7층 | 2900 | 781.384 | 0.0140649 | 0.0407883 | 2.26601 | 2.26601 | 0.0407883 | 80 | 0 | no | 지상 7층 | 2900 | 799.384 | 2.26601
7563535 | 지상 7층 | 2900 | 818.009 | 0.0147242 | 0.0427001 | 2.37223 | 2.37223 | 0.0427001 | 80 | 0 | no | 지상 7층 | 2900 | 840.259 | 2.37223
7563536 | 지상 7층 | 2900 | 710.367 | 0.0127866 | 0.0370812 | 2.06006 | 2.06006 | 0.0370812 | 80 | 0 | no | 지상 7층 | 2900 | 719.367 | 2.06006
7563537 | 지상 7층 | 2900 | 13392 | 0.241056 | 0.699063 | 38.8369 | 38.8369 | 0.699063 | 80 | 0 | no | 지상 7층 | 2900 | 13401 | 38.8369
7563538 | 지상 7층 | 2900 | 13392 | 0.241056 | 0.699062 | 38.8368 | 38.8368 | 0.699062 | 80 | 0 | no | 지상 7층 | 2900 | 13401 | 38.8368
7563539 | 지상 7층 | 2900 | 818.616 | 0.0147351 | 0.0427317 | 2.37399 | 2.37399 | 0.0427317 | 80 | 0 | no | 지상 7층 | 2900 | 809.616 | 2.37399
7563540 | 지상 7층 | 2900 | 737.5 | 0.013275 | 0.0384975 | 2.13875 | 2.13875 | 0.0384975 | 80 | 0 | no | 지상 7층 | 2900 | 737.5 | 2.13875
7563541 | 지상 7층 | 2900 | 11882 | 0.213876 | 0.620241 | 34.4579 | 34.4579 | 0.620241 | 80 | 0 | no | 지상 7층 | 2900 | 11882 | 34.4579
7563542 | 지상 7층 | 2900 | 737.525 | 0.0132754 | 0.0384988 | 2.13882 | 2.13882 | 0.0384988 | 80 | 0 | no | 지상 7층 | 2900 | 737.525 | 2.13882
7563543 | 지상 7층 | 2900 | 817.948 | 0.0147231 | 0.0426969 | 2.37205 | 2.37205 | 0.0426969 | 80 | 0 | no | 지상 7층 | 2900 | 817.948 | 2.37205
7563544 | 지상 7층 | 2900 | 710.041 | 0.0127807 | 0.0370641 | 2.05912 | 2.05912 | 0.0370641 | 80 | 0 | no | 지상 7층 | 2900 | 719.041 | 2.05912
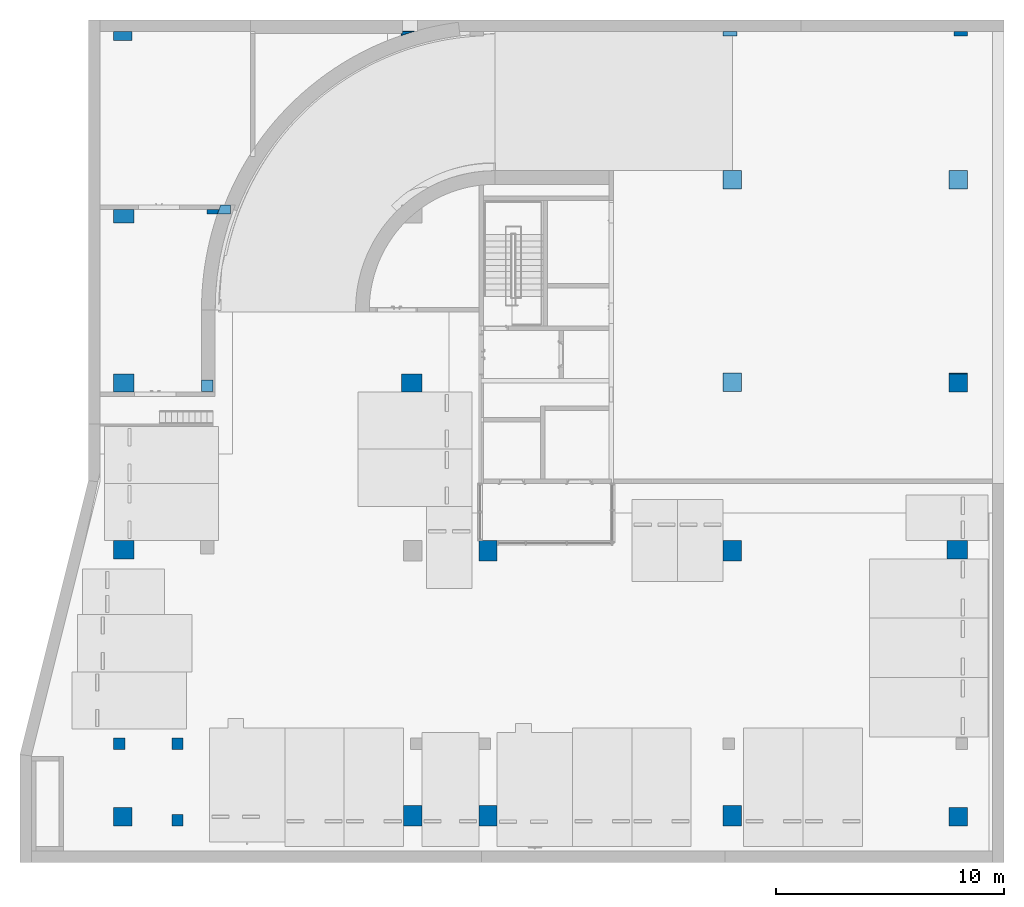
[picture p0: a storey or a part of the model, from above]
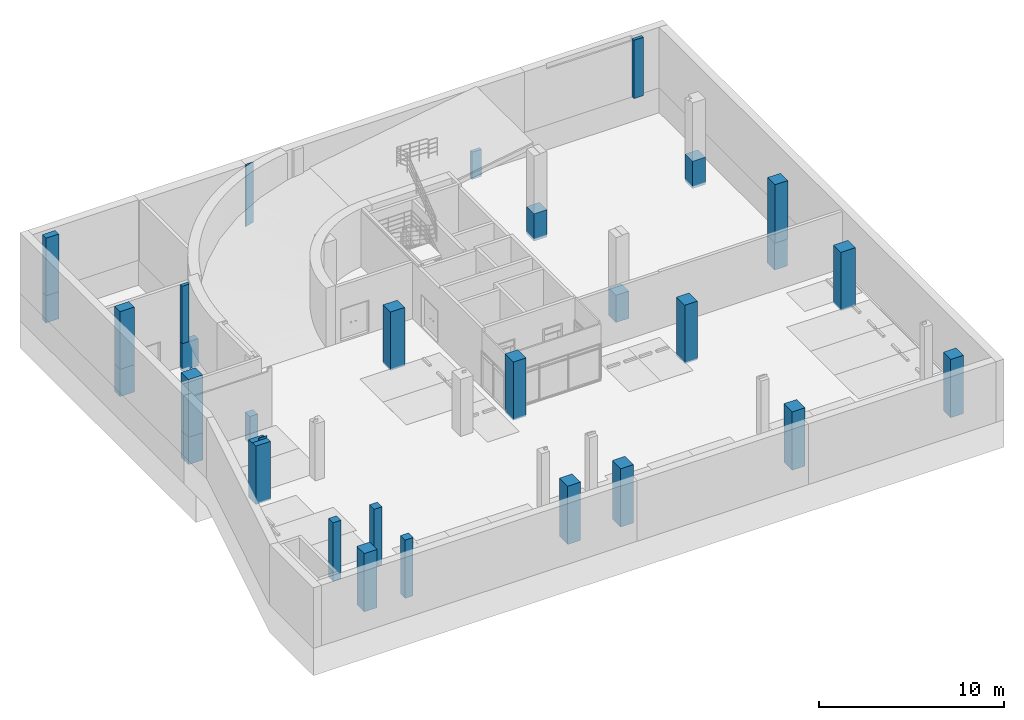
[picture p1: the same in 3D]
Properties of the parts of a building model (IFC2X3), part 36 of 39

# IfcWallStandardCase: 기본 벽:A1-32-06A-콘크리트면정리, 시멘트모르타르(미장용), 수성페인트(내부) (18mm) (773)
Name (기본 벽:A1-32-06A-콘크리트면정리, 시멘트모르타르(미장용), 수성페인트(내부) (18mm):...) | In | Height (mm) | Length (mm) | GrossFootprintArea (m2) | GrossVolume (m3) | GrossSideArea (m2) | NetSideArea (m2) | NetVolume (m3) = 체적 (m3) | 베이스 간격띄우기 (mm) | 상단 간격띄우기 (mm) | 상단이 부착됩니다. = ExtendToStructure | 베이스 구속조건 | 미연결 높이 (mm) | 길이 (mm) | 면적 (m2)
7563545 | 지상 7층 | 2900 | 12410 | 0.22338 | 0.647802 | 35.989 | 35.989 | 0.647802 | 80 | 0 | no | 지상 7층 | 2900 | 12410 | 35.989
7563546 | 지상 7층 | 2900 | 818 | 0.014724 | 0.0426996 | 2.3722 | 2.3722 | 0.0426996 | 80 | 0 | no | 지상 7층 | 2900 | 809 | 2.3722
7563547 | 지상 7층 | 2900 | 817.983 | 0.0147237 | 0.0426987 | 2.37215 | 2.37215 | 0.0426987 | 80 | 0 | no | 지상 7층 | 2900 | 817.983 | 2.37215
7563548 | 지상 7층 | 2900 | 800 | 0.0144 | 0.04176 | 2.32 | 2.32 | 0.04176 | 80 | 0 | no | 지상 7층 | 2900 | 809 | 2.32
7563549 | 지상 7층 | 2900 | 818.025 | 0.0147245 | 0.0427009 | 2.37227 | 2.37227 | 0.0427009 | 80 | 0 | no | 지상 7층 | 2900 | 809.025 | 2.37227
7563550 | 지상 7층 | 2900 | 800.615 | 0.0144111 | 0.0417921 | 2.32178 | 2.32178 | 0.0417921 | 80 | 0 | no | 지상 7층 | 2900 | 809.615 | 2.32178
7563551 | 지상 7층 | 2900 | 755.02 | 0.0135904 | 0.0394121 | 2.18956 | 2.18956 | 0.0394121 | 80 | 0 | no | 지상 7층 | 2900 | 737.02 | 2.18956
7563552 | 지상 7층 | 2900 | 710.026 | 0.0127805 | 0.0370633 | 2.05907 | 2.05907 | 0.0370633 | 80 | 0 | no | 지상 7층 | 2900 | 764.026 | 2.05907
7563553 | 지상 7층 | 2900 | 12392 | 0.223056 | 0.646862 | 35.9368 | 35.9368 | 0.646862 | 80 | 0 | no | 지상 7층 | 2900 | 12446 | 35.9368
7563554 | 지상 7층 | 2900 | 818 | 0.014724 | 0.0426996 | 2.3722 | 2.3722 | 0.0426996 | 80 | 0 | no | 지상 7층 | 2900 | 809 | 2.3722
7563555 | 지상 7층 | 2900 | 737.653 | 0.0132778 | 0.0385055 | 2.13919 | 2.13919 | 0.0385055 | 80 | 0 | no | 지상 7층 | 2900 | 737.653 | 2.13919
7563556 | 지상 7층 | 2900 | 10864 | 0.195552 | 0.567101 | 31.5056 | 31.5056 | 0.567101 | 80 | 0 | no | 지상 7층 | 2900 | 10882 | 31.5056
7563557 | 지상 7층 | 2900 | 10900 | 0.1962 | 0.56898 | 31.61 | 31.61 | 0.56898 | 80 | 0 | no | 지상 7층 | 2900 | 10882 | 31.61
7563558 | 지상 7층 | 2900 | 737.535 | 0.0132756 | 0.0384993 | 2.13885 | 2.13885 | 0.0384993 | 80 | 0 | no | 지상 7층 | 2900 | 737.535 | 2.13885
7563559 | 지상 7층 | 2900 | 710.026 | 0.0127805 | 0.0370633 | 2.05907 | 2.05907 | 0.0370633 | 80 | 0 | no | 지상 7층 | 2900 | 764.026 | 2.05907
7563561 | 지상 7층 | 2900 | 3910.04 | 0.0703808 | 0.204104 | 11.3391 | 11.3391 | 0.204104 | 80 | 0 | no | 지상 7층 | 2900 | 3892.04 | 11.3391
7563562 | 지상 7층 | 2900 | 500.009 | 0.00900016 | 0.0261005 | 1.45003 | 1.45003 | 0.0261005 | 80 | 0 | no | 지상 7층 | 2900 | 500.009 | 1.45003
7563563 | 지상 7층 | 2900 | 718 | 0.012924 | 0.0374796 | 2.0822 | 2.0822 | 0.0374796 | 80 | 0 | no | 지상 7층 | 2900 | 718 | 2.0822
7563564 | 지상 7층 | 2900 | 500.009 | 0.00900016 | 0.0261005 | 1.45003 | 1.45003 | 0.0261005 | 80 | 0 | no | 지상 7층 | 2900 | 500.009 | 1.45003
7563565 | 지상 7층 | 2900 | 8282 | 0.149076 | 0.43232 | 24.0178 | 24.0178 | 0.43232 | 80 | 0 | no | 지상 7층 | 2900 | 8282 | 24.0178
7563566 | 지상 7층 | 2900 | 500.009 | 0.00900016 | 0.0261005 | 1.45003 | 1.45003 | 0.0261005 | 80 | 0 | no | 지상 7층 | 2900 | 500.009 | 1.45003
7563567 | 지상 7층 | 2900 | 499.975 | 0.00899954 | 0.0260987 | 1.44993 | 1.44993 | 0.0260987 | 80 | 0 | no | 지상 7층 | 2900 | 499.975 | 1.44993
7563568 | 지상 7층 | 2900 | 9281.99 | 0.167076 | 0.48452 | 26.9178 | 23.3178 | 0.41972 | 0 | 0 | no | 지상 7층 | 2900 | 9281.99 | 23.3178
7563569 | 지상 7층 | 2900 | 499.975 | 0.00899954 | 0.0260987 | 1.44993 | 1.44993 | 0.0260987 | 80 | 0 | no | 지상 7층 | 2900 | 499.975 | 1.44993
7563570 | 지상 7층 | 2900 | 700 | 0.0126 | 0.03654 | 2.03 | 2.03 | 0.03654 | 80 | 0 | no | 지상 7층 | 2900 | 700 | 2.03
7563571 | 지상 7층 | 2900 | 699.983 | 0.0125997 | 0.0365391 | 2.02995 | 2.02995 | 0.0365391 | 80 | 0 | no | 지상 7층 | 2900 | 699.983 | 2.02995
7563572 | 지상 7층 | 2900 | 718.025 | 0.0129245 | 0.0374809 | 2.08227 | 2.08227 | 0.0374809 | 80 | 0 | no | 지상 7층 | 2900 | 718.025 | 2.08227
7563573 | 지상 7층 | 2900 | 681.983 | 0.0122757 | 0.0355995 | 1.97775 | 1.97775 | 0.0355995 | 80 | 0 | no | 지상 7층 | 2900 | 699.983 | 1.97775
7563574 | 지상 7층 | 2900 | 817.385 | 0.0147129 | 0.0426675 | 2.37042 | 2.37042 | 0.0426675 | 80 | 0 | no | 지상 7층 | 2900 | 808.385 | 2.37042
7563575 | 지상 7층 | 2900 | 818 | 0.014724 | 0.0426996 | 2.3722 | 2.3722 | 0.0426996 | 80 | 0 | no | 지상 7층 | 2900 | 818 | 2.3722
7563576 | 지상 7층 | 2900 | 799.376 | 0.0143888 | 0.0417274 | 2.31819 | 2.31819 | 0.0417274 | 80 | 0 | no | 지상 7층 | 2900 | 808.376 | 2.31819
7563577 | 지상 7층 | 2900 | 817.991 | 0.0147238 | 0.0426991 | 2.37217 | 2.37217 | 0.0426991 | 80 | 0 | no | 지상 7층 | 2900 | 808.991 | 2.37217
7563578 | 지상 7층 | 2900 | 800 | 0.0144 | 0.04176 | 2.32 | 2.32 | 0.04176 | 80 | 0 | no | 지상 7층 | 2900 | 809 | 2.32
7563579 | 지상 7층 | 2900 | 817.974 | 0.0147235 | 0.0426983 | 2.37213 | 2.37213 | 0.0426983 | 80 | 0 | no | 지상 7층 | 2900 | 883.974 | 2.37213
7563580 | 지상 7층 | 2900 | 719.5 | 0.012951 | 0.0375579 | 2.08655 | 2.08655 | 0.0375579 | 80 | 0 | no | 지상 7층 | 2900 | 737.5 | 2.08655
7563581 | 지상 7층 | 2900 | 7668.99 | 0.138042 | 0.400321 | 22.2401 | 22.2401 | 0.400321 | 80 | 0 | no | 지상 7층 | 2900 | 7686.99 | 22.2401
7563584 | 지상 8층 | 4100 | 2582.01 | 0.0464762 | 0.190552 | 10.5862 | 10.5862 | 0.190552 | 0 | 0 | no | 지상 8층 | 4100 | 2582.01 | 10.5862 | 구속조건 - 상단 구속조건: 상위 레벨: 지상 9층
7563585 | 지상 8층 | 2900 | 5482 | 0.098676 | 0.28616 | 15.8978 | 13.5878 | 0.24458 | 0 | 0 | no | 지상 8층 | 2900 | 5482 | 13.5878
7563586 | 지상 8층 | 4100 | 2582.01 | 0.0464762 | 0.190552 | 10.5862 | 10.5862 | 0.190552 | 0 | 0 | no | 지상 8층 | 4100 | 2582.01 | 10.5862 | 구속조건 - 상단 구속조건: 상위 레벨: 지상 9층
7563587 | 지상 8층 | 4100 | 5482 | 0.098676 | 0.404572 | 22.4762 | 22.4762 | 0.404572 | 0 | 0 | no | 지상 8층 | 4100 | 5482 | 22.4762 | 구속조건 - 상단 구속조건: 상위 레벨: 지상 9층
7563588 | 지상 8층 | 4100 | 2582.01 | 0.0464762 | 0.190552 | 10.5862 | 10.5862 | 0.190552 | 0 | 0 | no | 지상 8층 | 4100 | 2582.01 | 10.5862 | 구속조건 - 상단 구속조건: 상위 레벨: 지상 9층
7563589 | 지상 8층 | 4100 | 5482 | 0.098676 | 0.404572 | 22.4762 | 22.4762 | 0.404572 | 0 | 0 | no | 지상 8층 | 4100 | 5482 | 22.4762 | 구속조건 - 상단 구속조건: 상위 레벨: 지상 9층
7563590 | 지상 8층 | 4100 | 2582.01 | 0.0464762 | 0.190552 | 10.5862 | 6.80624 | 0.122512 | 0 | 0 | no | 지상 8층 | 4100 | 2582.01 | 6.80624 | 구속조건 - 상단 구속조건: 상위 레벨: 지상 9층
7563591 | 지상 8층 | 4100 | 5482 | 0.098676 | 0.404572 | 22.4762 | 22.4762 | 0.404572 | 0 | 0 | no | 지상 8층 | 4100 | 5482 | 22.4762 | 구속조건 - 상단 구속조건: 상위 레벨: 지상 9층
7563592 | 지상 8층 | 2900 | 3282.01 | 0.0590762 | 0.171321 | 9.51783 | 9.51783 | 0.171321 | 0 | 0 | no | 지상 8층 | 2900 | 3282.01 | 9.51783
7563593 | 지상 8층 | 2900 | 2082 | 0.037476 | 0.10868 | 6.0378 | 4.1478 | 0.0746604 | 0 | 0 | no | 지상 8층 | 2900 | 2082 | 4.1478
7563594 | 지상 8층 | 2900 | 3282.01 | 0.0590762 | 0.171321 | 9.51783 | 9.51783 | 0.171321 | 0 | 0 | no | 지상 8층 | 2900 | 3282.01 | 9.51783
7563595 | 지상 8층 | 2900 | 2082 | 0.037476 | 0.10868 | 6.0378 | 3.2328 | 0.0581904 | 0 | 0 | no | 지상 8층 | 2900 | 2082 | 3.2328
7563600 | 지상 8층 | 2900 | 7399.97 | 0.1332 | 0.0432 | 2.4 | 19.0599 | 0.343079 | 80 | 0 | no | 지상 8층 | 2900 | 7435.97 | 19.0599
7563601 | 지상 8층 | 2900 | 400 | 0.0072 | 0.02088 | 1.16 | 1.16 | 0.02088 | 80 | 0 | no | 지상 8층 | 2900 | 400 | 1.16
7563602 | 지상 8층 | 2900 | 400.025 | 0.00720046 | 0.0208813 | 1.16007 | 1.16007 | 0.0208813 | 80 | 0 | no | 지상 8층 | 2900 | 400.025 | 1.16007
7563603 | 지상 8층 | 2900 | 2082.01 | 0.0374762 | 0.108681 | 6.03783 | 6.03783 | 0.108681 | 80 | 0 | no | 지상 8층 | 2900 | 2082.01 | 6.03783
7563604 | 지상 8층 | 2900 | 500 | 0.009 | 0.0261 | 1.45 | 1.45 | 0.0261 | 80 | 0 | no | 지상 8층 | 2900 | 500 | 1.45
7563605 | 지상 8층 | 2900 | 717.983 | 0.0129237 | 0.0374787 | 2.08215 | 2.08215 | 0.0374787 | 80 | 0 | no | 지상 8층 | 2900 | 717.983 | 2.08215
7563606 | 지상 8층 | 2900 | 500 | 0.009 | 0.0261 | 1.45 | 1.45 | 0.0261 | 80 | 0 | no | 지상 8층 | 2900 | 500 | 1.45
7563607 | 지상 8층 | 2900 | 12082 | 0.217476 | 0.63068 | 35.0378 | 31.4378 | 0.56588 | 80 | 0 | no | 지상 8층 | 2900 | 12082 | 31.4378
7563609 | 지상 8층 | 2900 | 718.017 | 0.0129243 | 0.0374805 | 2.08225 | 2.08225 | 0.0374805 | 80 | 0 | no | 지상 8층 | 2900 | 784.017 | 2.08225
7563610 | 지상 8층 | 2900 | 13500.6 | 0.243011 | 0.704732 | 39.1518 | 39.1518 | 0.704732 | 80 | 0 | no | 지상 8층 | 2900 | 13500.6 | 39.1518
7563611 | 지상 8층 | 2900 | 627.983 | 0.0113037 | 0.0327807 | 1.82115 | 1.82115 | 0.0327807 | 80 | 0 | no | 지상 8층 | 2900 | 618.983 | 1.82115
7563612 | 지상 8층 | 2900 | 637.475 | 0.0114745 | 0.0332762 | 1.84868 | 1.84868 | 0.0332762 | 80 | 0 | no | 지상 8층 | 2900 | 637.475 | 1.84868
7563613 | 지상 8층 | 2900 | 12082 | 0.217476 | 0.630681 | 35.0379 | 35.0379 | 0.630681 | 80 | 0 | no | 지상 8층 | 2900 | 12082 | 35.0379
7563614 | 지상 8층 | 2900 | 637.475 | 0.0114745 | 0.0332762 | 1.84868 | 1.84868 | 0.0332762 | 80 | 0 | no | 지상 8층 | 2900 | 637.475 | 1.84868
7563615 | 지상 8층 | 2900 | 681.983 | 0.0122757 | 0.0355995 | 1.97775 | 1.97775 | 0.0355995 | 80 | 0 | no | 지상 8층 | 2900 | 699.983 | 1.97775
7563619 | 지상 8층 | 2900 | 709.025 | 0.0127625 | 0.0370111 | 2.05617 | 2.05617 | 0.0370111 | 80 | 0 | no | 지상 8층 | 2900 | 700.025 | 2.05617
7563620 | 지상 8층 | 2900 | 609.983 | 0.0109797 | 0.0318411 | 1.76895 | 1.76895 | 0.0318411 | 80 | 0 | no | 지상 8층 | 2900 | 618.983 | 1.76895
7563621 | 지상 8층 | 2900 | 13392 | 0.241056 | 0.699061 | 38.8367 | 38.8367 | 0.699061 | 80 | 0 | no | 지상 8층 | 2900 | 13401 | 38.8367
7563622 | 지상 8층 | 2900 | 13392 | 0.241056 | 0.699061 | 38.8367 | 38.8367 | 0.699061 | 80 | 0 | no | 지상 8층 | 2900 | 13401 | 38.8367
7563623 | 지상 8층 | 2900 | 718.616 | 0.0129351 | 0.0375117 | 2.08399 | 2.08399 | 0.0375117 | 80 | 0 | no | 지상 8층 | 2900 | 709.616 | 2.08399
7563624 | 지상 8층 | 2900 | 637.499 | 0.011475 | 0.0332775 | 1.84875 | 1.84875 | 0.0332775 | 80 | 0 | no | 지상 8층 | 2900 | 637.499 | 1.84875
7563625 | 지상 8층 | 2900 | 12082 | 0.217476 | 0.630681 | 35.0379 | 35.0379 | 0.630681 | 80 | 0 | no | 지상 8층 | 2900 | 12082 | 35.0379
7563626 | 지상 8층 | 2900 | 637.5 | 0.011475 | 0.0332775 | 1.84875 | 1.84875 | 0.0332775 | 80 | 0 | no | 지상 8층 | 2900 | 637.5 | 1.84875
7563627 | 지상 8층 | 2900 | 717.367 | 0.0129126 | 0.0374466 | 2.08036 | 2.08036 | 0.0374466 | 80 | 0 | no | 지상 8층 | 2900 | 717.367 | 2.08036
7563628 | 지상 8층 | 2900 | 604.975 | 0.0108895 | 0.0315797 | 1.75443 | 1.75443 | 0.0315797 | 80 | 0 | no | 지상 8층 | 2900 | 613.975 | 1.75443
7563629 | 지상 8층 | 2900 | 12410 | 0.22338 | 0.647802 | 35.989 | 35.989 | 0.647802 | 80 | 0 | no | 지상 8층 | 2900 | 12410 | 35.989
7563630 | 지상 8층 | 2900 | 718.025 | 0.0129244 | 0.0374809 | 2.08227 | 2.08227 | 0.0374809 | 80 | 0 | no | 지상 8층 | 2900 | 709.025 | 2.08227
7563631 | 지상 8층 | 2900 | 718.017 | 0.0129243 | 0.0374805 | 2.08225 | 2.08225 | 0.0374805 | 80 | 0 | no | 지상 8층 | 2900 | 718.017 | 2.08225
7563632 | 지상 8층 | 2900 | 700.025 | 0.0126004 | 0.0365413 | 2.03007 | 2.03007 | 0.0365413 | 80 | 0 | no | 지상 8층 | 2900 | 709.025 | 2.03007
7563633 | 지상 8층 | 2900 | 718.025 | 0.0129245 | 0.0374809 | 2.08227 | 2.08227 | 0.0374809 | 80 | 0 | no | 지상 8층 | 2900 | 709.025 | 2.08227
7563634 | 지상 8층 | 2900 | 700.615 | 0.0126111 | 0.0365721 | 2.03178 | 2.03178 | 0.0365721 | 80 | 0 | no | 지상 8층 | 2900 | 709.615 | 2.03178
7563635 | 지상 8층 | 2900 | 655.517 | 0.0117993 | 0.034218 | 1.901 | 1.901 | 0.034218 | 80 | 0 | no | 지상 8층 | 2900 | 637.517 | 1.901
7563636 | 지상 8층 | 2900 | 609.983 | 0.0109797 | 0.0318411 | 1.76895 | 1.76895 | 0.0318411 | 80 | 0 | no | 지상 8층 | 2900 | 663.983 | 1.76895
7563637 | 지상 8층 | 2900 | 12392 | 0.223056 | 0.646861 | 35.9367 | 35.9367 | 0.646861 | 80 | 0 | no | 지상 8층 | 2900 | 12446 | 35.9367
7563638 | 지상 8층 | 2900 | 718.025 | 0.0129244 | 0.0374809 | 2.08227 | 2.08227 | 0.0374809 | 80 | 0 | no | 지상 8층 | 2900 | 709.025 | 2.08227
7563639 | 지상 8층 | 2900 | 637.517 | 0.0114753 | 0.0332784 | 1.8488 | 1.8488 | 0.0332784 | 80 | 0 | no | 지상 8층 | 2900 | 637.517 | 1.8488
7563640 | 지상 8층 | 2900 | 11064 | 0.199152 | 0.577541 | 32.0856 | 32.0856 | 0.577541 | 80 | 0 | no | 지상 8층 | 2900 | 11082 | 32.0856
7563641 | 지상 8층 | 2900 | 11100 | 0.1998 | 0.57942 | 32.19 | 32.19 | 0.57942 | 80 | 0 | no | 지상 8층 | 2900 | 11082 | 32.19
7563642 | 지상 8층 | 2900 | 637.517 | 0.0114753 | 0.0332784 | 1.8488 | 1.8488 | 0.0332784 | 80 | 0 | no | 지상 8층 | 2900 | 637.517 | 1.8488
7563643 | 지상 8층 | 2900 | 610 | 0.01098 | 0.031842 | 1.769 | 1.769 | 0.031842 | 80 | 0 | no | 지상 8층 | 2900 | 619 | 1.769
7563645 | 지상 8층 | 2900 | 3910 | 0.07038 | 0.204102 | 11.339 | 11.339 | 0.204102 | 80 | 0 | no | 지상 8층 | 2900 | 3892 | 11.339
7563646 | 지상 8층 | 2900 | 500.009 | 0.00900016 | 0.0261005 | 1.45003 | 1.45003 | 0.0261005 | 80 | 0 | no | 지상 8층 | 2900 | 500.009 | 1.45003
7563647 | 지상 8층 | 2900 | 718 | 0.012924 | 0.0374796 | 2.0822 | 2.0822 | 0.0374796 | 80 | 0 | no | 지상 8층 | 2900 | 718 | 2.0822
7563648 | 지상 8층 | 2900 | 500.009 | 0.00900016 | 0.0261005 | 1.45003 | 1.45003 | 0.0261005 | 80 | 0 | no | 지상 8층 | 2900 | 500.009 | 1.45003
7563649 | 지상 8층 | 2900 | 8282 | 0.149076 | 0.43232 | 24.0178 | 24.0178 | 0.43232 | 80 | 0 | no | 지상 8층 | 2900 | 8282 | 24.0178
7563650 | 지상 8층 | 2900 | 499.376 | 0.00898876 | 0.0260674 | 1.44819 | 1.44819 | 0.0260674 | 80 | 0 | no | 지상 8층 | 2900 | 499.376 | 1.44819
7563651 | 지상 8층 | 2900 | 499.975 | 0.00899954 | 0.0260987 | 1.44993 | 1.44993 | 0.0260987 | 80 | 0 | no | 지상 8층 | 2900 | 499.975 | 1.44993
7563652 | 지상 8층 | 2900 | 9282.62 | 0.167087 | 0.484553 | 26.9196 | 23.3196 | 0.419753 | 0 | 0 | no | 지상 8층 | 2900 | 9282.62 | 23.3196
7563653 | 지상 8층 | 2900 | 499.975 | 0.00899954 | 0.0260987 | 1.44993 | 1.44993 | 0.0260987 | 80 | 0 | no | 지상 8층 | 2900 | 499.975 | 1.44993
7563654 | 지상 8층 | 2900 | 700.008 | 0.0126001 | 0.0365404 | 2.03002 | 2.03002 | 0.0365404 | 80 | 0 | no | 지상 8층 | 2900 | 700.008 | 2.03002
7563655 | 지상 8층 | 2900 | 699.991 | 0.0125998 | 0.0365395 | 2.02997 | 2.02997 | 0.0365395 | 80 | 0 | no | 지상 8층 | 2900 | 699.991 | 2.02997
7563656 | 지상 8층 | 2900 | 717.025 | 0.0129065 | 0.0374287 | 2.07937 | 2.07937 | 0.0374287 | 80 | 0 | no | 지상 8층 | 2900 | 717.025 | 2.07937
7563657 | 지상 8층 | 2900 | 681.991 | 0.0122758 | 0.0355999 | 1.97777 | 1.97777 | 0.0355999 | 80 | 0 | no | 지상 8층 | 2900 | 699.991 | 1.97777
7563658 | 지상 8층 | 2900 | 717.367 | 0.0129126 | 0.0374466 | 2.08036 | 2.08036 | 0.0374466 | 80 | 0 | no | 지상 8층 | 2900 | 708.367 | 2.08036
7563659 | 지상 8층 | 2900 | 717.975 | 0.0129235 | 0.0374783 | 2.08213 | 2.08213 | 0.0374783 | 80 | 0 | no | 지상 8층 | 2900 | 717.975 | 2.08213
7563660 | 지상 8층 | 2900 | 699.358 | 0.0125885 | 0.0365065 | 2.02814 | 2.02814 | 0.0365065 | 80 | 0 | no | 지상 8층 | 2900 | 708.358 | 2.02814
7563661 | 지상 8층 | 2900 | 718.008 | 0.0129241 | 0.03748 | 2.08222 | 2.08222 | 0.03748 | 80 | 0 | no | 지상 8층 | 2900 | 709.008 | 2.08222
7563662 | 지상 8층 | 2900 | 700.025 | 0.0126005 | 0.0365413 | 2.03007 | 2.03007 | 0.0365413 | 80 | 0 | no | 지상 8층 | 2900 | 709.025 | 2.03007
7563663 | 지상 8층 | 2900 | 718 | 0.012924 | 0.0374796 | 2.0822 | 2.0822 | 0.0374796 | 80 | 0 | no | 지상 8층 | 2900 | 784 | 2.0822
7563664 | 지상 8층 | 2900 | 619.517 | 0.0111513 | 0.0323388 | 1.7966 | 1.7966 | 0.0323388 | 80 | 0 | no | 지상 8층 | 2900 | 637.517 | 1.7966
7563665 | 지상 8층 | 2900 | 7669 | 0.138042 | 0.400322 | 22.2401 | 22.2401 | 0.400322 | 80 | 0 | no | 지상 8층 | 2900 | 7687 | 22.2401
7565258 | 지상 8층 | 2900 | 482 | 0.008676 | 0.0251604 | 1.3978 | 1.3978 | 0.0251604 | 80 | 0 | no | 지상 8층 | 2900 | 500 | 1.3978
7567220 | 지상 9층 | 2900 | 5500 | 0.095519 | 0.2871 | 15.95 | 13.64 | 0.236887 | 0 | 0 | no | 지상 9층 | 2900 | 5482 | 13.64
7567227 | 지상 9층 | 2900 | 3282.01 | 0.0590762 | 0.171321 | 9.51783 | 9.51783 | 0.171321 | 0 | 0 | no | 지상 9층 | 2900 | 3282.01 | 9.51783
7567228 | 지상 9층 | 2900 | 2082 | 0.0361583 | 0.10868 | 6.0378 | 4.1478 | 0.0720352 | 0 | 0 | no | 지상 9층 | 2900 | 2082 | 4.1478
7567229 | 지상 9층 | 2900 | 3282.01 | 0.0590762 | 0.171321 | 9.51783 | 9.51783 | 0.171321 | 0 | 0 | no | 지상 9층 | 2900 | 3282.01 | 9.51783
7567230 | 지상 9층 | 2900 | 2082 | 0.037476 | 0.10868 | 6.0378 | 3.2328 | 0.0581904 | 0 | 0 | no | 지상 9층 | 2900 | 2082 | 3.2328
7567235 | 지상 9층 | 2900 | 4450 | 0.0801 | 0.23229 | 12.905 | 10.505 | 0.18909 | 80 | 0 | no | 지상 9층 | 2900 | 4541 | 10.505
7567236 | 지상 9층 | 2900 | 400.017 | 0.00720031 | 0.0208809 | 1.16005 | 1.16005 | 0.0208809 | 80 | 0 | no | 지상 9층 | 2900 | 400.017 | 1.16005
7567237 | 지상 9층 | 2900 | 400 | 0.00719999 | 0.02088 | 1.16 | 1.16 | 0.02088 | 80 | 0 | no | 지상 9층 | 2900 | 400 | 1.16
7567238 | 지상 9층 | 2900 | 2081.97 | 0.0374755 | 0.108679 | 6.03772 | 6.03772 | 0.108679 | 80 | 0 | no | 지상 9층 | 2900 | 2081.97 | 6.03772
7567239 | 지상 9층 | 2900 | 500 | 0.009 | 0.0261 | 1.45 | 1.45 | 0.0261 | 80 | 0 | no | 지상 9층 | 2900 | 500 | 1.45
7567240 | 지상 9층 | 2900 | 718.017 | 0.0129243 | 0.0374805 | 2.08225 | 2.08225 | 0.0374805 | 80 | 0 | no | 지상 9층 | 2900 | 718.017 | 2.08225
7567241 | 지상 9층 | 2900 | 500 | 0.009 | 0.0261 | 1.45 | 1.45 | 0.0261 | 80 | 0 | no | 지상 9층 | 2900 | 500 | 1.45
7567242 | 지상 9층 | 2900 | 4481.98 | 0.0806757 | 0.233959 | 12.9977 | 12.9977 | 0.233959 | 80 | 0 | no | 지상 9층 | 2900 | 4490.98 | 12.9977
7567243 | 지상 9층 | 2900 | 8.97461 | 0.000161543 | 0.0009396 | 0.0522 | 0.0522 | 0.000468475 | 80 | 0 | no | 지상 9층 | 2900 | 8.97461 | 0.0260264
7567244 | 지상 9층 | 2900 | 718 | 0.012924 | 0.0374796 | 2.0822 | 2.0822 | 0.0374796 | 80 | 0 | no | 지상 9층 | 2900 | 700 | 2.0822
7567245 | 지상 9층 | 2900 | 13410 | 0.24138 | 0.700002 | 38.889 | 38.889 | 0.700002 | 80 | 0 | no | 지상 9층 | 2900 | 13410 | 38.889
7567246 | 지상 9층 | 2900 | 617.375 | 0.0111127 | 0.032227 | 1.79039 | 1.79039 | 0.032227 | 80 | 0 | no | 지상 9층 | 2900 | 608.375 | 1.79039
7567247 | 지상 9층 | 2900 | 637.5 | 0.011475 | 0.0332775 | 1.84875 | 1.84875 | 0.0332775 | 80 | 0 | no | 지상 9층 | 2900 | 637.5 | 1.84875
7567248 | 지상 9층 | 2900 | 12082 | 0.217476 | 0.630681 | 35.0379 | 35.0379 | 0.630681 | 80 | 0 | no | 지상 9층 | 2900 | 12082 | 35.0379
7567249 | 지상 9층 | 2900 | 637.5 | 0.011475 | 0.0332775 | 1.84875 | 1.84875 | 0.0332775 | 80 | 0 | no | 지상 9층 | 2900 | 637.5 | 1.84875
7567250 | 지상 9층 | 2900 | 700 | 0.0126 | 0.03654 | 2.03 | 2.03 | 0.03654 | 80 | 0 | no | 지상 9층 | 2900 | 700 | 2.03
7567254 | 지상 9층 | 2900 | 718 | 0.012924 | 0.0374796 | 2.0822 | 2.0822 | 0.0374796 | 80 | 0 | no | 지상 9층 | 2900 | 740.25 | 2.0822
7567255 | 지상 9층 | 2900 | 609.983 | 0.0109797 | 0.0318411 | 1.76895 | 1.76895 | 0.0318411 | 80 | 0 | no | 지상 9층 | 2900 | 618.983 | 1.76895
7567256 | 지상 9층 | 2900 | 13375 | 0.24075 | 0.698175 | 38.7875 | 38.7875 | 0.698175 | 80 | 0 | no | 지상 9층 | 2900 | 13375 | 38.7875
7567257 | 지상 9층 | 2900 | 13392.3 | 0.241061 | 0.699077 | 38.8376 | 38.8376 | 0.699077 | 80 | 0 | no | 지상 9층 | 2900 | 13401.3 | 38.8376
7567258 | 지상 9층 | 2900 | 718.616 | 0.0129351 | 0.0375117 | 2.08399 | 2.08399 | 0.0375117 | 80 | 0 | no | 지상 9층 | 2900 | 709.616 | 2.08399
7567259 | 지상 9층 | 2900 | 637.499 | 0.011475 | 0.0332775 | 1.84875 | 1.84875 | 0.0332775 | 80 | 0 | no | 지상 9층 | 2900 | 637.499 | 1.84875
7567260 | 지상 9층 | 2900 | 12082 | 0.217476 | 0.630681 | 35.0379 | 35.0379 | 0.630681 | 80 | 0 | no | 지상 9층 | 2900 | 12082 | 35.0379
7567261 | 지상 9층 | 2900 | 637.5 | 0.011475 | 0.0332775 | 1.84875 | 1.84875 | 0.0332775 | 80 | 0 | no | 지상 9층 | 2900 | 637.5 | 1.84875
7567262 | 지상 9층 | 2900 | 717.367 | 0.0129126 | 0.0374466 | 2.08036 | 2.08036 | 0.0374466 | 80 | 0 | no | 지상 9층 | 2900 | 717.367 | 2.08036
7567263 | 지상 9층 | 2900 | 556 | 0.010008 | 0.0290232 | 1.6124 | 1.6124 | 0.0290232 | 80 | 0 | no | 지상 9층 | 2900 | 565 | 1.6124
7567264 | 지상 9층 | 2900 | 12355 | 0.22239 | 0.644932 | 35.8296 | 35.8296 | 0.644932 | 80 | 0 | no | 지상 9층 | 2900 | 12355 | 35.8296
7567265 | 지상 9층 | 2900 | 718.025 | 0.0129244 | 0.0374809 | 2.08227 | 2.08227 | 0.0374809 | 80 | 0 | no | 지상 9층 | 2900 | 709.025 | 2.08227
7567266 | 지상 9층 | 2900 | 717.983 | 0.0129237 | 0.0374787 | 2.08215 | 2.08215 | 0.0374787 | 80 | 0 | no | 지상 9층 | 2900 | 717.983 | 2.08215
7567267 | 지상 9층 | 2900 | 700.025 | 0.0126004 | 0.0365413 | 2.03007 | 2.03007 | 0.0365413 | 80 | 0 | no | 지상 9층 | 2900 | 709.025 | 2.03007
7567268 | 지상 9층 | 2900 | 718.025 | 0.0129245 | 0.0374809 | 2.08227 | 2.08227 | 0.0374809 | 80 | 0 | no | 지상 9층 | 2900 | 709.025 | 2.08227
7567269 | 지상 9층 | 2900 | 700.615 | 0.0126111 | 0.0365721 | 2.03178 | 2.03178 | 0.0365721 | 80 | 0 | no | 지상 9층 | 2900 | 709.615 | 2.03178
7567270 | 지상 9층 | 2900 | 655.517 | 0.0117993 | 0.034218 | 1.901 | 1.901 | 0.034218 | 80 | 0 | no | 지상 9층 | 2900 | 637.517 | 1.901
7567271 | 지상 9층 | 2900 | 555 | 0.00999001 | 0.028971 | 1.6095 | 1.6095 | 0.028971 | 80 | 0 | no | 지상 9층 | 2900 | 564 | 1.6095
7567272 | 지상 9층 | 2900 | 12378 | 0.222804 | 0.64613 | 35.8961 | 35.8961 | 0.64613 | 80 | 0 | no | 지상 9층 | 2900 | 12387 | 35.8961
7567273 | 지상 9층 | 2900 | 718.025 | 0.0129244 | 0.0374809 | 2.08227 | 2.08227 | 0.0374809 | 80 | 0 | no | 지상 9층 | 2900 | 709.025 | 2.08227
7567274 | 지상 9층 | 2900 | 637.517 | 0.0114753 | 0.0332784 | 1.8488 | 1.8488 | 0.0332784 | 80 | 0 | no | 지상 9층 | 2900 | 637.517 | 1.8488
7567275 | 지상 9층 | 2900 | 11064 | 0.199152 | 0.577541 | 32.0856 | 32.0856 | 0.577541 | 80 | 0 | no | 지상 9층 | 2900 | 11082 | 32.0856
7567276 | 지상 9층 | 2900 | 11100 | 0.1998 | 0.57942 | 32.19 | 32.19 | 0.57942 | 80 | 0 | no | 지상 9층 | 2900 | 11082 | 32.19
7567277 | 지상 9층 | 2900 | 637.517 | 0.0114753 | 0.0332784 | 1.8488 | 1.8488 | 0.0332784 | 80 | 0 | no | 지상 9층 | 2900 | 637.517 | 1.8488
7567278 | 지상 9층 | 2900 | 555 | 0.00999001 | 0.028971 | 1.6095 | 1.6095 | 0.028971 | 80 | 0 | no | 지상 9층 | 2900 | 564 | 1.6095
7567279 | 지상 9층 | 2900 | 4.02498 | 0.0000724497 | 0.0009396 | 0.0522 | 0.0522 | 0.000210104 | 80 | 0 | no | 지상 9층 | 2900 | 2649.02 | 0.0116724
7567280 | 지상 9층 | 2900 | 3854.98 | 0.0693896 | 0.20123 | 11.1794 | 11.1794 | 0.20123 | 80 | 0 | no | 지상 9층 | 2900 | 3845.98 | 11.1794
7567281 | 지상 9층 | 2900 | 500.642 | 0.00901155 | 0.0261335 | 1.45186 | 1.45186 | 0.0261335 | 80 | 0 | no | 지상 9층 | 2900 | 500.642 | 1.45186
7567282 | 지상 9층 | 2900 | 718.025 | 0.0129245 | 0.0374809 | 2.08227 | 2.08227 | 0.0374809 | 80 | 0 | no | 지상 9층 | 2900 | 718.025 | 2.08227
7567283 | 지상 9층 | 2900 | 500.642 | 0.00901155 | 0.0261335 | 1.45186 | 1.45186 | 0.0261335 | 80 | 0 | no | 지상 9층 | 2900 | 500.642 | 1.45186
7567284 | 지상 9층 | 2900 | 8282 | 0.149076 | 0.43232 | 24.0178 | 24.0178 | 0.43232 | 80 | 0 | no | 지상 9층 | 2900 | 8282 | 24.0178
7567285 | 지상 9층 | 2900 | 500.009 | 0.00900016 | 0.0261005 | 1.45003 | 1.45003 | 0.0261005 | 80 | 0 | no | 지상 9층 | 2900 | 500.009 | 1.45003
7567286 | 지상 9층 | 2900 | 499.975 | 0.00899954 | 0.0260987 | 1.44993 | 1.44993 | 0.0260987 | 80 | 0 | no | 지상 9층 | 2900 | 499.975 | 1.44993
7567287 | 지상 9층 | 2900 | 9282.01 | 0.167076 | 0.484521 | 26.9178 | 23.3178 | 0.419721 | 0 | 0 | no | 지상 9층 | 2900 | 9282.01 | 23.3178
7567288 | 지상 9층 | 2900 | 499.975 | 0.00899954 | 0.0260987 | 1.44993 | 1.44993 | 0.0260987 | 80 | 0 | no | 지상 9층 | 2900 | 499.975 | 1.44993
7567289 | 지상 9층 | 2900 | 682.624 | 0.0122872 | 0.035633 | 1.97961 | 1.97961 | 0.035633 | 80 | 0 | no | 지상 9층 | 2900 | 700.624 | 1.97961
7567290 | 지상 9층 | 2900 | 699.991 | 0.0125998 | 0.0365395 | 2.02997 | 2.02997 | 0.0365395 | 80 | 0 | no | 지상 9층 | 2900 | 699.991 | 2.02997
7567291 | 지상 9층 | 2900 | 717.025 | 0.0129065 | 0.0374287 | 2.07937 | 2.07937 | 0.0374287 | 80 | 0 | no | 지상 9층 | 2900 | 717.025 | 2.07937
7567292 | 지상 9층 | 2900 | 681.991 | 0.0122758 | 0.0355999 | 1.97777 | 1.97777 | 0.0355999 | 80 | 0 | no | 지상 9층 | 2900 | 699.991 | 1.97777
7567293 | 지상 9층 | 2900 | 717.367 | 0.0129126 | 0.0374466 | 2.08036 | 2.08036 | 0.0374466 | 80 | 0 | no | 지상 9층 | 2900 | 708.367 | 2.08036
7567294 | 지상 9층 | 2900 | 717.975 | 0.0129235 | 0.0374783 | 2.08213 | 2.08213 | 0.0374783 | 80 | 0 | no | 지상 9층 | 2900 | 717.975 | 2.08213
7567295 | 지상 9층 | 2900 | 699.358 | 0.0125885 | 0.0365065 | 2.02814 | 2.02814 | 0.0365065 | 80 | 0 | no | 지상 9층 | 2900 | 708.358 | 2.02814
7567296 | 지상 9층 | 2900 | 717.367 | 0.0129126 | 0.0374466 | 2.08036 | 2.08036 | 0.0374466 | 80 | 0 | no | 지상 9층 | 2900 | 708.367 | 2.08036
7567297 | 지상 9층 | 2900 | 700.025 | 0.0126005 | 0.0365413 | 2.03007 | 2.03007 | 0.0365413 | 80 | 0 | no | 지상 9층 | 2900 | 709.025 | 2.03007
7567298 | 지상 9층 | 2900 | 718 | 0.012924 | 0.0374796 | 2.0822 | 2.0822 | 0.0374796 | 80 | 0 | no | 지상 9층 | 2900 | 784 | 2.0822
7567299 | 지상 9층 | 2900 | 619.5 | 0.011151 | 0.0323379 | 1.79655 | 1.79655 | 0.0323379 | 80 | 0 | no | 지상 9층 | 2900 | 637.5 | 1.79655
7567300 | 지상 9층 | 2900 | 7687 | 0.138366 | 0.401261 | 22.2923 | 22.2923 | 0.401261 | 80 | 0 | no | 지상 9층 | 2900 | 7741 | 22.2923
7567301 | 지상 9층 | 2900 | 7687.01 | 0.138366 | 0.401262 | 22.2923 | 22.2923 | 0.401262 | 80 | 0 | no | 지상 9층 | 2900 | 10591 | 22.2923
7567302 | 지상 9층 | 2900 | 482 | 0.008676 | 0.0251604 | 1.3978 | 1.3978 | 0.0251604 | 80 | 0 | no | 지상 9층 | 2900 | 500 | 1.3978
7568165 | 지상 1층 | 30 | 2498.17 | 0.0449671 | 0.00134901 | 0.0749451 | 0.0749451 | 0.00134901 | 80 | -1170 | no | 지상 1층 | 3550 | 2643.17 | 0.0749451 | 구속조건 - 상단 구속조건: 상위 레벨: 지상 2층
7568166 | 지상 1층 | 3500 | 12047.5 | 0.216855 | 0.343193 | 19.0663 | 19.0663 | 0.343193 | 80 | -1220 | no | 지상 1층 | 3500 | 12047.5 | 19.0663 | 구속조건 - 상단 구속조건: 상위 레벨: 지상 2층
7568167 | 지상 1층 | 3500 | 13500 | 0.243 | 0.8505 | 47.25 | 47.25 | 0.8505 | 80 | -1220 | no | 지상 1층 | 3500 | 13549 | 47.25 | 구속조건 - 상단 구속조건: 상위 레벨: 지상 2층
7568168 | 지상 1층 | 3500 | 918.017 | 0.0165243 | 0.0578351 | 3.21306 | 3.21306 | 0.0578351 | 80 | -1220 | no | 지상 1층 | 3500 | 949.017 | 3.21306 | 구속조건 - 상단 구속조건: 상위 레벨: 지상 2층
7568171 | 지상 1층 | 4130 | 21237.5 | 0.382275 | 1.5788 | 87.7108 | 21.1828 | 0.381291 | -500 | -1170 | no | 지상 1층 | 4130 | 21246.5 | 21.1828 | 구속조건 - 상단 구속조건: 상위 레벨: 지상 2층
7568172 | 지상 1층 | 4130 | 13355.3 | 0.240395 | 0.540348 | 30.0193 | 30.0193 | 0.540348 | -500 | -1170 | no | 지상 1층 | 4130 | 13346.3 | 30.0193 | 구속조건 - 상단 구속조건: 상위 레벨: 지상 2층
7568173 | 지상 1층 | 4130 | 11300 | 0.2034 | 0.840043 | 46.6691 | 41.8691 | 0.753643 | -500 | -1170 | no | 지상 1층 | 4130 | 11300 | 41.8691 | 구속조건 - 상단 구속조건: 상위 레벨: 지상 2층
7568174 | 지상 1층 | 4130 | 4618.02 | 0.0831243 | 0.343303 | 19.0724 | 16.9724 | 0.305503 | -500 | -1170 | no | 지상 1층 | 4130 | 4600.02 | 16.9724 | 구속조건 - 상단 구속조건: 상위 레벨: 지상 2층
7568175 | 지상 1층 | 4130 | 499.991 | 0.00899984 | 0.0371694 | 2.06496 | 2.06496 | 0.0371694 | -500 | -1170 | no | 지상 1층 | 4130 | 608.991 | 2.06496 | 구속조건 - 상단 구속조건: 상위 레벨: 지상 2층
7568176 | 지상 1층 | 4130 | 6703.91 | 0.12067 | 0.498369 | 27.6871 | 26.6471 | 0.479649 | -500 | -1170 | no | 지상 1층 | 4130 | 6703.91 | 26.6471 | 구속조건 - 상단 구속조건: 상위 레벨: 지상 2층
7568177 | 지상 1층 | 3630 | 5919.85 | 0.106557 | 0.386803 | 21.489 | 15.879 | 0.285823 | 0 | -1170 | no | 지상 1층 | 3630 | 5919.85 | 15.879 | 구속조건 - 상단 구속조건: 상위 레벨: 지상 2층
7568178 | 지상 1층 | 3550 | 15933.9 | 0.28681 | 0.942576 | 52.3653 | 52.3653 | 0.942576 | 80 | -1170 | no | 지상 1층 | 3550 | 15942.9 | 52.3653 | 구속조건 - 상단 구속조건: 상위 레벨: 지상 2층
7568179 | 지상 1층 | 3500 | 11800 | 0.2124 | 0.603 | 33.5 | 33.5 | 0.603 | 80 | -1220 | no | 지상 1층 | 3500 | 11782 | 33.5 | 구속조건 - 상단 구속조건: 상위 레벨: 지상 2층
7568180 | 지상 1층 | 3500 | 600 | 0.0108 | 0.0378 | 2.1 | 2.1 | 0.0378 | 80 | -1220 | no | 지상 1층 | 3500 | 600 | 2.1 | 구속조건 - 상단 구속조건: 상위 레벨: 지상 2층
7568181 | 지상 1층 | 3500 | 918 | 0.016524 | 0.057834 | 3.213 | 3.213 | 0.057834 | 80 | -1220 | no | 지상 1층 | 3500 | 918 | 3.213 | 구속조건 - 상단 구속조건: 상위 레벨: 지상 2층
7568182 | 지상 1층 | 3500 | 600.017 | 0.0108003 | 0.0378011 | 2.10006 | 2.10006 | 0.0378011 | 80 | -1220 | no | 지상 1층 | 3500 | 709.017 | 2.10006 | 구속조건 - 상단 구속조건: 상위 레벨: 지상 2층
7568183 | 지상 1층 | 3500 | 2081.99 | 0.0374758 | 0.131165 | 7.28697 | 7.28697 | 0.131165 | 80 | -1220 | no | 지상 1층 | 3500 | 2081.99 | 7.28697 | 구속조건 - 상단 구속조건: 상위 레벨: 지상 2층
7568184 | 지상 1층 | 3500 | 400.017 | 0.00720031 | 0.0252011 | 1.40006 | 1.40006 | 0.0252011 | 80 | -1220 | no | 지상 1층 | 3500 | 400.017 | 1.40006 | 구속조건 - 상단 구속조건: 상위 레벨: 지상 2층
7568185 | 지상 1층 | 3500 | 398.162 | 0.00716692 | 0.0250842 | 1.39357 | 1.39357 | 0.0250842 | 80 | -1220 | no | 지상 1층 | 3500 | 507.162 | 1.39357 | 구속조건 - 상단 구속조건: 상위 레벨: 지상 2층
7568186 | 지상 1층 | 3500 | 3452.02 | 0.0621363 | 0.217477 | 12.0821 | 9.68206 | 0.174277 | 80 | -1220 | no | 지상 1층 | 3500 | 3461.02 | 9.68206 | 구속조건 - 상단 구속조건: 상위 레벨: 지상 2층
7568187 | 지상 1층 | 3500 | 13285 | 0.23913 | 0.836955 | 46.4975 | 46.4975 | 0.836955 | 80 | -1220 | no | 지상 1층 | 3500 | 13392.5 | 46.4975 | 구속조건 - 상단 구속조건: 상위 레벨: 지상 2층
7568188 | 지상 1층 | 3500 | 693.017 | 0.0124743 | 0.0436601 | 2.42556 | 2.42556 | 0.0436601 | 80 | -1220 | no | 지상 1층 | 3500 | 746.517 | 2.42556 | 구속조건 - 상단 구속조건: 상위 레벨: 지상 2층
7568189 | 지상 1층 | 3500 | 581.983 | 0.0104757 | 0.0366649 | 2.03694 | 2.03694 | 0.0366649 | 80 | -1220 | no | 지상 1층 | 3500 | 599.983 | 2.03694 | 구속조건 - 상단 구속조건: 상위 레벨: 지상 2층
7568190 | 지상 1층 | 3500 | 13285 | 0.23913 | 0.836955 | 46.4975 | 46.4975 | 0.836955 | 80 | -1220 | no | 지상 1층 | 3500 | 13392.5 | 46.4975 | 구속조건 - 상단 구속조건: 상위 레벨: 지상 2층
7568192 | 지상 1층 | 3500 | 13281.8 | 0.239073 | 0.836756 | 46.4864 | 46.4864 | 0.836756 | 80 | -1220 | no | 지상 1층 | 3500 | 13344.3 | 46.4864 | 구속조건 - 상단 구속조건: 상위 레벨: 지상 2층
7568194 | 지상 1층 | 3500 | 3264.03 | 0.0587526 | 0.205634 | 11.4241 | 11.4241 | 0.205634 | 80 | -1220 | no | 지상 1층 | 3500 | 3282.03 | 11.4241 | 구속조건 - 상단 구속조건: 상위 레벨: 지상 2층
7568195 | 지상 1층 | 3500 | 827.983 | 0.0149037 | 0.0521629 | 2.89794 | 2.89794 | 0.0521629 | 80 | -1220 | no | 지상 1층 | 3500 | 863.983 | 2.89794 | 구속조건 - 상단 구속조건: 상위 레벨: 지상 2층
7568196 | 지상 1층 | 3500 | 719.518 | 0.0129513 | 0.0453296 | 2.51831 | 2.51831 | 0.0453296 | 80 | -1220 | no | 지상 1층 | 3500 | 737.518 | 2.51831 | 구속조건 - 상단 구속조건: 상위 레벨: 지상 2층
7568197 | 지상 1층 | 3500 | 11700 | 0.2106 | 0.7371 | 40.95 | 40.95 | 0.7371 | 80 | -1220 | no | 지상 1층 | 3500 | 11682 | 40.95 | 구속조건 - 상단 구속조건: 상위 레벨: 지상 2층
7568198 | 지상 1층 | 3500 | 737.518 | 0.0132753 | 0.0464636 | 2.58131 | 2.58131 | 0.0464636 | 80 | -1220 | no | 지상 1층 | 3500 | 737.518 | 2.58131 | 구속조건 - 상단 구속조건: 상위 레벨: 지상 2층
7568199 | 지상 1층 | 3500 | 775.633 | 0.0139614 | 0.0488649 | 2.71471 | 2.71471 | 0.0488649 | 80 | -1220 | no | 지상 1층 | 3500 | 847.133 | 2.71471 | 구속조건 - 상단 구속조건: 상위 레벨: 지상 2층
7568200 | 지상 1층 | 3500 | 793.633 | 0.0142854 | 0.0499989 | 2.77771 | 2.77771 | 0.0499989 | 80 | -1220 | no | 지상 1층 | 3500 | 847.133 | 2.77771 | 구속조건 - 상단 구속조건: 상위 레벨: 지상 2층
7568201 | 지상 1층 | 3500 | 800.017 | 0.0144003 | 0.0504011 | 2.80006 | 2.80006 | 0.0504011 | 80 | -1220 | no | 지상 1층 | 3500 | 840.267 | 2.80006 | 구속조건 - 상단 구속조건: 상위 레벨: 지상 2층
7568202 | 지상 1층 | 3500 | 11682 | 0.210276 | 0.735966 | 40.887 | 40.887 | 0.735966 | 80 | -1220 | no | 지상 1층 | 3500 | 11682 | 40.887 | 구속조건 - 상단 구속조건: 상위 레벨: 지상 2층
7568203 | 지상 1층 | 3500 | 800.035 | 0.0144006 | 0.0504022 | 2.80012 | 2.80012 | 0.0504022 | 80 | -1220 | no | 지상 1층 | 3500 | 800.035 | 2.80012 | 구속조건 - 상단 구속조건: 상위 레벨: 지상 2층
7568204 | 지상 1층 | 3500 | 809.983 | 0.0145797 | 0.0510289 | 2.83494 | 2.83494 | 0.0510289 | 80 | -1220 | no | 지상 1층 | 3500 | 818.983 | 2.83494 | 구속조건 - 상단 구속조건: 상위 레벨: 지상 2층
7568205 | 지상 1층 | 3500 | 3259.73 | 0.0586752 | 0.205363 | 11.4091 | 11.4091 | 0.205363 | 80 | -1220 | no | 지상 1층 | 3500 | 3259.73 | 11.4091 | 구속조건 - 상단 구속조건: 상위 레벨: 지상 2층
7568206 | 지상 1층 | 3500 | 13248.1 | 0.238466 | 0.834631 | 46.3684 | 46.3684 | 0.834631 | 80 | -1220 | no | 지상 1층 | 3500 | 13293.1 | 46.3684 | 구속조건 - 상단 구속조건: 상위 레벨: 지상 2층
7568207 | 지상 1층 | 3500 | 655.018 | 0.0117903 | 0.0412661 | 2.29256 | 2.29256 | 0.0412661 | 80 | -1220 | no | 지상 1층 | 3500 | 655.018 | 2.29256 | 구속조건 - 상단 구속조건: 상위 레벨: 지상 2층
7568208 | 지상 1층 | 3500 | 775.017 | 0.0139503 | 0.0488261 | 2.71256 | 2.71256 | 0.0488261 | 80 | -1220 | no | 지상 1층 | 3500 | 846.517 | 2.71256 | 구속조건 - 상단 구속조건: 상위 레벨: 지상 2층
7568210 | 지상 1층 | 3500 | 755 | 0.01359 | 0.047565 | 2.6425 | 2.6425 | 0.047565 | 80 | -1220 | no | 지상 1층 | 3500 | 755 | 2.6425 | 구속조건 - 상단 구속조건: 상위 레벨: 지상 2층
7568211 | 지상 1층 | 3500 | 708.983 | 0.0127617 | 0.0446659 | 2.48144 | 2.48144 | 0.0446659 | 80 | -1220 | no | 지상 1층 | 3500 | 717.983 | 2.48144 | 구속조건 - 상단 구속조건: 상위 레벨: 지상 2층
7568213 | 지상 1층 | 3550 | 8299.99 | 0.1494 | 0.530369 | 29.465 | 29.465 | 0.530369 | 80 | -1170 | no | 지상 1층 | 3550 | 8299.99 | 29.465 | 구속조건 - 상단 구속조건: 상위 레벨: 지상 2층
7568214 | 지상 1층 | 3500 | 13175.1 | 0.237153 | 0.830034 | 46.113 | 46.113 | 0.830034 | 80 | -1220 | no | 지상 1층 | 3500 | 13184.1 | 46.113 | 구속조건 - 상단 구속조건: 상위 레벨: 지상 2층
7568216 | 지상 1층 | 3500 | 13192.1 | 0.237459 | 0.831105 | 46.1725 | 46.1725 | 0.831105 | 80 | -1220 | no | 지상 1층 | 3500 | 13192.1 | 46.1725 | 구속조건 - 상단 구속조건: 상위 레벨: 지상 2층
7568217 | 지상 1층 | 3500 | 13248.1 | 0.238466 | 0.834631 | 46.3684 | 46.3684 | 0.834631 | 80 | -1220 | no | 지상 1층 | 3500 | 13293.1 | 46.3684 | 구속조건 - 상단 구속조건: 상위 레벨: 지상 2층
7568219 | 지상 1층 | 3500 | 727.983 | 0.0131037 | 0.0458629 | 2.54794 | 2.54794 | 0.0458629 | 80 | -1220 | no | 지상 1층 | 3500 | 763.983 | 2.54794 | 구속조건 - 상단 구속조건: 상위 레벨: 지상 2층
7568220 | 지상 1층 | 3500 | 774.982 | 0.0139497 | 0.0488239 | 2.71244 | 2.71244 | 0.0488239 | 80 | -1220 | no | 지상 1층 | 3500 | 846.482 | 2.71244 | 구속조건 - 상단 구속조건: 상위 레벨: 지상 2층
7568222 | 지상 1층 | 3500 | 12192.5 | 0.219465 | 0.768128 | 42.6738 | 42.6738 | 0.768128 | 80 | -1220 | no | 지상 1층 | 3500 | 12192.5 | 42.6738 | 구속조건 - 상단 구속조건: 상위 레벨: 지상 2층
7568224 | 지상 1층 | 3500 | 775.017 | 0.0139503 | 0.0488261 | 2.71256 | 2.71256 | 0.0488261 | 80 | -1220 | no | 지상 1층 | 3500 | 775.017 | 2.71256 | 구속조건 - 상단 구속조건: 상위 레벨: 지상 2층
7568225 | 지상 1층 | 3500 | 655 | 0.01179 | 0.041265 | 2.2925 | 2.2925 | 0.041265 | 80 | -1220 | no | 지상 1층 | 3500 | 664 | 2.2925 | 구속조건 - 상단 구속조건: 상위 레벨: 지상 2층
7568227 | 지상 1층 | 3500 | 672 | 0.012096 | 0.042336 | 2.352 | 2.352 | 0.042336 | 80 | -1220 | no | 지상 1층 | 3500 | 663 | 2.352 | 구속조건 - 상단 구속조건: 상위 레벨: 지상 2층
7568228 | 지상 1층 | 3500 | 754.018 | 0.0135723 | 0.0475031 | 2.63906 | 2.63906 | 0.0475031 | 80 | -1220 | no | 지상 1층 | 3500 | 763.018 | 2.63906 | 구속조건 - 상단 구속조건: 상위 레벨: 지상 2층
7568230 | 지상 1층 | 3500 | 809.018 | 0.0145623 | 0.0509681 | 2.83156 | 2.83156 | 0.0509681 | 80 | -1220 | no | 지상 1층 | 3500 | 809.018 | 2.83156 | 구속조건 - 상단 구속조건: 상위 레벨: 지상 2층
7568231 | 지상 1층 | 3500 | 500 | 0.009 | 0.0315 | 1.75 | 1.75 | 0.0315 | 80 | -1220 | no | 지상 1층 | 3500 | 477.75 | 1.75 | 구속조건 - 상단 구속조건: 상위 레벨: 지상 2층
7568232 | 지상 1층 | 3500 | 10683 | 0.192294 | 0.673028 | 37.3904 | 37.3904 | 0.673028 | 80 | -1220 | no | 지상 1층 | 3500 | 10683 | 37.3904 | 구속조건 - 상단 구속조건: 상위 레벨: 지상 2층
7568233 | 지상 1층 | 3500 | 437.5 | 0.007875 | 0.0275625 | 1.53125 | 1.53125 | 0.0275625 | 80 | -1220 | no | 지상 1층 | 3500 | 437.5 | 1.53125 | 구속조건 - 상단 구속조건: 상위 레벨: 지상 2층
7568234 | 지상 1층 | 3500 | 775 | 0.01395 | 0.048825 | 2.7125 | 2.7125 | 0.048825 | 80 | -1220 | no | 지상 1층 | 3500 | 846.5 | 2.7125 | 구속조건 - 상단 구속조건: 상위 레벨: 지상 2층
7568236 | 지상 1층 | 3500 | 12192.5 | 0.219465 | 0.768128 | 42.6738 | 42.6738 | 0.768128 | 80 | -1220 | no | 지상 1층 | 3500 | 12192.5 | 42.6738 | 구속조건 - 상단 구속조건: 상위 레벨: 지상 2층
7568238 | 지상 1층 | 3500 | 608.965 | 0.0109614 | 0.0383648 | 2.13138 | 2.13138 | 0.0383648 | 80 | -1220 | no | 지상 1층 | 3500 | 599.965 | 2.13138 | 구속조건 - 상단 구속조건: 상위 레벨: 지상 2층
7568239 | 지상 1층 | 3500 | 737.491 | 0.0132748 | 0.046462 | 2.58122 | 2.58122 | 0.046462 | 80 | -1220 | no | 지상 1층 | 3500 | 746.491 | 2.58122 | 구속조건 - 상단 구속조건: 상위 레벨: 지상 2층
7568240 | 지상 1층 | 3500 | 10019.5 | 0.180351 | 0.631228 | 35.0682 | 35.0682 | 0.631228 | 80 | -1220 | no | 지상 1층 | 3500 | 10028.5 | 35.0682 | 구속조건 - 상단 구속조건: 상위 레벨: 지상 2층
7568241 | 지상 1층 | 3500 | 3300.03 | 0.0594006 | 0.207902 | 11.5501 | 11.5501 | 0.207902 | 80 | -1220 | no | 지상 1층 | 3500 | 3282.03 | 11.5501 | 구속조건 - 상단 구속조건: 상위 레벨: 지상 2층
7568242 | 지상 1층 | 3500 | 300 | 0.0054 | 0.0189 | 1.05 | 1.05 | 0.0189 | 80 | -1220 | no | 지상 1층 | 3500 | 300 | 1.05 | 구속조건 - 상단 구속조건: 상위 레벨: 지상 2층
7568243 | 지상 1층 | 3500 | 690.965 | 0.0124374 | 0.0435308 | 2.41838 | 2.41838 | 0.0435308 | 80 | -1220 | no | 지상 1층 | 3500 | 699.965 | 2.41838 | 구속조건 - 상단 구속조건: 상위 레벨: 지상 2층
7568244 | 지상 1층 | 3500 | 10040.8 | 0.180734 | 0.63257 | 35.1428 | 35.1428 | 0.63257 | 80 | -1220 | no | 지상 1층 | 3500 | 10031.8 | 35.1428 | 구속조건 - 상단 구속조건: 상위 레벨: 지상 2층
7568245 | 지상 1층 | 3500 | 10037.5 | 0.180675 | 0.632362 | 35.1312 | 35.1312 | 0.632362 | 80 | -1220 | no | 지상 1층 | 3500 | 10068.7 | 35.1312 | 구속조건 - 상단 구속조건: 상위 레벨: 지상 2층
7568246 | 지상 1층 | 3500 | 4002.5 | 0.072045 | 0.252158 | 14.0088 | 14.0088 | 0.252158 | 80 | -1220 | no | 지상 1층 | 3500 | 4020.5 | 14.0088 | 구속조건 - 상단 구속조건: 상위 레벨: 지상 2층
7568247 | 지상 1층 | 3500 | 10037.5 | 0.180675 | 0.632362 | 35.1312 | 35.1312 | 0.632362 | 80 | -1220 | no | 지상 1층 | 3500 | 10068.7 | 35.1312 | 구속조건 - 상단 구속조건: 상위 레벨: 지상 2층
7568248 | 지상 1층 | 3500 | 692.991 | 0.0124738 | 0.0436585 | 2.42547 | 2.42547 | 0.0436585 | 80 | -1220 | no | 지상 1층 | 3500 | 746.491 | 2.42547 | 구속조건 - 상단 구속조건: 상위 레벨: 지상 2층
7568249 | 지상 1층 | 3500 | 674.982 | 0.0121497 | 0.0425239 | 2.36244 | 2.36244 | 0.0425239 | 80 | -1220 | no | 지상 1층 | 3500 | 746.482 | 2.36244 | 구속조건 - 상단 구속조건: 상위 레벨: 지상 2층
7568250 | 지상 1층 | 3500 | 18 | 0.000324 | 0.001134 | 0.063 | 0.063 | 0.001134 | 80 | -1220 | no | 지상 1층 | 3500 | 9082 | 0.063 | 구속조건 - 상단 구속조건: 상위 레벨: 지상 2층
7568251 | 지상 1층 | 3500 | 775 | 0.01395 | 0.048825 | 2.7125 | 2.7125 | 0.048825 | 80 | -1220 | no | 지상 1층 | 3500 | 775 | 2.7125 | 구속조건 - 상단 구속조건: 상위 레벨: 지상 2층
7568252 | 지상 1층 | 3500 | 300 | 0.0054 | 0.0189 | 1.05 | 1.05 | 0.0189 | 80 | -1220 | no | 지상 1층 | 3500 | 300 | 1.05 | 구속조건 - 상단 구속조건: 상위 레벨: 지상 2층
7568253 | 지상 1층 | 3500 | 3201.47 | 0.0576264 | 0.201692 | 11.2051 | 11.2051 | 0.201692 | 80 | -1220 | no | 지상 1층 | 3500 | 3219.47 | 11.2051 | 구속조건 - 상단 구속조건: 상위 레벨: 지상 2층
7568254 | 지상 1층 | 4080 | 3837.5 | 0.069075 | 0.281826 | 15.657 | 15.657 | 0.281826 | -500 | -1220 | no | 지상 1층 | 4080 | 3928.5 | 15.657 | 구속조건 - 상단 구속조건: 상위 레벨: 지상 2층
7568255 | 지상 1층 | 4080 | 10357 | 0.186426 | 0.30584 | 16.9911 | 16.9911 | 0.30584 | -500 | -1220 | no | 지상 1층 | 4080 | 10428.5 | 16.9911 | 구속조건 - 상단 구속조건: 상위 레벨: 지상 2층
7568256 | 지상 1층 | 4080 | 600.009 | 0.0108002 | 0.0440646 | 2.44804 | 2.44804 | 0.0440646 | -500 | -1220 | no | 지상 1층 | 4080 | 600.009 | 2.44804 | 구속조건 - 상단 구속조건: 상위 레벨: 지상 2층
7568257 | 지상 1층 | 4080 | 800 | 0.0144 | 0.058752 | 3.264 | 3.264 | 0.058752 | -500 | -1220 | no | 지상 1층 | 4080 | 840.25 | 3.264 | 구속조건 - 상단 구속조건: 상위 레벨: 지상 2층
7568258 | 지상 1층 | 4080 | 9082.01 | 0.163476 | 0.666983 | 37.0546 | 37.0546 | 0.666983 | -500 | -1220 | no | 지상 1층 | 4080 | 9082.01 | 37.0546 | 구속조건 - 상단 구속조건: 상위 레벨: 지상 2층
7568259 | 지상 1층 | 4080 | 800.018 | 0.0144003 | 0.0587533 | 3.26407 | 3.26407 | 0.0587533 | -500 | -1220 | no | 지상 1층 | 4080 | 800.018 | 3.26407 | 구속조건 - 상단 구속조건: 상위 레벨: 지상 2층
7568260 | 지상 1층 | 4080 | 674.983 | 0.0121497 | 0.0495707 | 2.75393 | 2.75393 | 0.0495707 | -500 | -1220 | no | 지상 1층 | 4080 | 683.983 | 2.75393 | 구속조건 - 상단 구속조건: 상위 레벨: 지상 2층
7568262 | 지상 1층 | 5080 | 10337.5 | 0.186075 | 0.945263 | 52.5146 | 52.5146 | 0.945263 | -1500 | -1220 | no | 지상 1층 | 5080 | 10437.5 | 52.5146 | 구속조건 - 상단 구속조건: 상위 레벨: 지상 2층
7568263 | 지상 1층 | 5080 | 4119.47 | 0.0741504 | 0.376684 | 20.9269 | 20.9269 | 0.376684 | -1500 | -1220 | no | 지상 1층 | 5080 | 4159.72 | 20.9269 | 구속조건 - 상단 구속조건: 상위 레벨: 지상 2층
7568264 | 지상 1층 | 5080 | 10357 | 0.186426 | 0.947046 | 52.6136 | 52.6136 | 0.947046 | -1500 | -1220 | no | 지상 1층 | 5080 | 10428.5 | 52.6136 | 구속조건 - 상단 구속조건: 상위 레벨: 지상 2층
7568265 | 지상 1층 | 5080 | 10337.5 | 0.186075 | 0.945263 | 52.5146 | 52.5146 | 0.945263 | -1500 | -1220 | no | 지상 1층 | 5080 | 10437.5 | 52.5146 | 구속조건 - 상단 구속조건: 상위 레벨: 지상 2층
7568266 | 지상 1층 | 5080 | 3783.02 | 0.0680943 | 0.345919 | 19.2177 | 19.2177 | 0.345919 | -1500 | -1220 | no | 지상 1층 | 5080 | 3783.02 | 19.2177 | 구속조건 - 상단 구속조건: 상위 레벨: 지상 2층
7568267 | 지상 1층 | 5080 | 600.009 | 0.0108002 | 0.0548648 | 3.04804 | 3.04804 | 0.0548648 | -1500 | -1220 | no | 지상 1층 | 5080 | 600.009 | 3.04804 | 구속조건 - 상단 구속조건: 상위 레벨: 지상 2층
7568268 | 지상 1층 | 5080 | 600.017 | 0.0108003 | 0.0548656 | 3.04809 | 3.04809 | 0.0548656 | -1500 | -1220 | no | 지상 1층 | 5080 | 709.017 | 3.04809 | 구속조건 - 상단 구속조건: 상위 레벨: 지상 2층
7568269 | 지상 1층 | 5080 | 9083.01 | 0.163494 | 0.83055 | 46.1417 | 42.5417 | 0.76575 | -1500 | -1220 | no | 지상 1층 | 5080 | 9083.01 | 42.5417 | 구속조건 - 상단 구속조건: 상위 레벨: 지상 2층
7568270 | 지상 1층 | 5080 | 599.982 | 0.0107997 | 0.0548624 | 3.04791 | 3.04791 | 0.0548624 | -1500 | -1220 | no | 지상 1층 | 5080 | 599.982 | 3.04791 | 구속조건 - 상단 구속조건: 상위 레벨: 지상 2층
7568271 | 지상 1층 | 5080 | 675 | 0.01215 | 0.061722 | 3.429 | 3.429 | 0.061722 | -1500 | -1220 | no | 지상 1층 | 5080 | 746.5 | 3.429 | 구속조건 - 상단 구속조건: 상위 레벨: 지상 2층
7568272 | 지상 1층 | 3500 | 3319.85 | 0.0597572 | 0.20915 | 11.6195 | 11.6195 | 0.20915 | 80 | -1220 | no | 지상 1층 | 3500 | 3301.85 | 11.6195 | 구속조건 - 상단 구속조건: 상위 레벨: 지상 2층
7568273 | 지상 1층 | 3500 | 2081.98 | 0.0374757 | 0.0806749 | 4.48194 | 4.48194 | 0.0806749 | 80 | -1220 | no | 지상 1층 | 3500 | 2190.98 | 4.48194 | 구속조건 - 상단 구속조건: 상위 레벨: 지상 2층
7568274 | 지상 1층 | 3500 | 3283.85 | 0.0591092 | 0.206882 | 11.4935 | 11.4935 | 0.206882 | 80 | -1220 | no | 지상 1층 | 3500 | 3392.85 | 11.4935 | 구속조건 - 상단 구속조건: 상위 레벨: 지상 2층
7568275 | 지상 1층 | 3500 | 2064 | 0.037152 | 0.096012 | 5.334 | 5.334 | 0.096012 | 80 | -1220 | no | 지상 1층 | 3500 | 2082 | 5.334 | 구속조건 - 상단 구속조건: 상위 레벨: 지상 2층
7568276 | 지상 1층 | 4800 | 5500 | 0.099 | 0.4752 | 26.4 | 24.09 | 0.43362 | 0 | 0 | no | 지상 1층 | 4800 | 5482 | 24.09 | 구속조건 - 상단 구속조건: 상위 레벨: 지상 2층
7568277 | 지상 1층 | 4800 | 2582.01 | 0.0464762 | 0.223086 | 12.3936 | 12.3936 | 0.223086 | 0 | 0 | no | 지상 1층 | 4800 | 2582.01 | 12.3936 | 구속조건 - 상단 구속조건: 상위 레벨: 지상 2층
7568278 | 지상 1층 | 4800 | 5482 | 0.098676 | 0.473645 | 26.3136 | 26.3136 | 0.473645 | 0 | 0 | no | 지상 1층 | 4800 | 5482 | 26.3136 | 구속조건 - 상단 구속조건: 상위 레벨: 지상 2층
7568279 | 지하1층 | 6100 | 5500 | 0.099 | 0.6039 | 33.55 | 33.55 | 0.6039 | 0 | 0 | no | 지하1층 | 6100 | 5482 | 33.55 | 구속조건 - 상단 구속조건: 상위 레벨: 지상 1층
7568280 | 지하1층 | 6100 | 2582.01 | 0.0464762 | 0.242605 | 13.478 | 13.478 | 0.242605 | 0 | 0 | no | 지하1층 | 6100 | 2582.01 | 13.478 | 구속조건 - 상단 구속조건: 상위 레벨: 지상 1층
7568281 | 지하1층 | 6100 | 5482 | 0.098676 | 0.601924 | 33.4402 | 33.4402 | 0.601924 | 0 | 0 | no | 지하1층 | 6100 | 5482 | 33.4402 | 구속조건 - 상단 구속조건: 상위 레벨: 지상 1층
7568282 | 지상 1층 | 4800 | 2564.01 | 0.0461522 | 0.22153 | 12.3072 | 12.3072 | 0.22153 | 0 | 0 | no | 지상 1층 | 4800 | 2582.01 | 12.3072 | 구속조건 - 상단 구속조건: 상위 레벨: 지상 2층
7568283 | 지하1층 | 6100 | 2564.01 | 0.0461522 | 0.281528 | 15.6405 | 15.6405 | 0.281528 | 0 | 0 | no | 지하1층 | 6100 | 2582.01 | 15.6405 | 구속조건 - 상단 구속조건: 상위 레벨: 지상 1층
7568284 | 지상 1층 | 4800 | 2582.01 | 0.0464762 | 0.223086 | 12.3936 | 12.3936 | 0.223086 | 0 | 0 | no | 지상 1층 | 4800 | 2582.01 | 12.3936 | 구속조건 - 상단 구속조건: 상위 레벨: 지상 2층
7568285 | 지상 1층 | 4800 | 2600.01 | 0.0468002 | 0.224641 | 12.48 | 12.48 | 0.224641 | 0 | 0 | no | 지상 1층 | 4800 | 2582.01 | 12.48 | 구속조건 - 상단 구속조건: 상위 레벨: 지상 2층
7568286 | 지상 1층 | 4800 | 5482 | 0.098676 | 0.473645 | 26.3136 | 26.3136 | 0.473645 | 0 | 0 | no | 지상 1층 | 4800 | 5482 | 26.3136 | 구속조건 - 상단 구속조건: 상위 레벨: 지상 2층
7568287 | 지상 1층 | 4800 | 5464 | 0.098352 | 0.430511 | 23.9173 | 23.9173 | 0.430511 | 0 | 0 | no | 지상 1층 | 4800 | 5482 | 23.9173 | 구속조건 - 상단 구속조건: 상위 레벨: 지상 2층
7568890 | 지상 1층 | 3550 | 836 | 0.015048 | 0.0534204 | 2.9678 | 2.9678 | 0.0534204 | 80 | -1170 | no | 지상 1층 | 3550 | 818 | 2.9678 | 구속조건 - 상단 구속조건: 상위 레벨: 지상 2층
7570458 | 지상 1층 | 3500 | 11801 | 0.212418 | 0.743463 | 41.3035 | 41.3035 | 0.743463 | 80 | -1220 | no | 지상 1층 | 3500 | 11783 | 41.3035 | 구속조건 - 상단 구속조건: 상위 레벨: 지상 2층
7570835 | 지상 1층 | 3500 | 13138.1 | 0.236487 | 0.827703 | 45.9835 | 45.9835 | 0.827703 | 80 | -1220 | no | 지상 1층 | 3500 | 13138.1 | 45.9835 | 구속조건 - 상단 구속조건: 상위 레벨: 지상 2층
7571195 | 지상 1층 | 3500 | 693.017 | 0.0124743 | 0.0436601 | 2.42556 | 2.42556 | 0.0436601 | 80 | -1220 | no | 지상 1층 | 3500 | 746.517 | 2.42556 | 구속조건 - 상단 구속조건: 상위 레벨: 지상 2층
7571196 | 지상 1층 | 3500 | 675 | 0.01215 | 0.042525 | 2.3625 | 2.3625 | 0.042525 | 80 | -1220 | no | 지상 1층 | 3500 | 746.5 | 2.3625 | 구속조건 - 상단 구속조건: 상위 레벨: 지상 2층
7575410 | 옥탑층 | 3500 | 2573.01 | 0.0463142 | 0.1621 | 9.00553 | 9.00553 | 0.1621 | 0 | -500 | no | 옥탑층 | 3500 | 2582.01 | 9.00553 | 구속조건 - 상단 구속조건: 상위 레벨: 지붕층
7575411 | 옥탑층 | 3500 | 2591.01 | 0.0466382 | 0.163234 | 9.06853 | 9.06853 | 0.163234 | 0 | -500 | no | 옥탑층 | 3500 | 2582.01 | 9.06853 | 구속조건 - 상단 구속조건: 상위 레벨: 지붕층
7575412 | 옥탑층 | 3500 | 5482 | 0.098676 | 0.345366 | 19.187 | 19.187 | 0.345366 | 0 | -500 | no | 옥탑층 | 3500 | 5482 | 19.187 | 구속조건 - 상단 구속조건: 상위 레벨: 지붕층
7576668 | 옥탑층 | 3500 | 2600.01 | 0.0468002 | 0.163801 | 9.10003 | 9.10003 | 0.163801 | 0 | -500 | no | 옥탑층 | 3500 | 2582.01 | 9.10003 | 구속조건 - 상단 구속조건: 상위 레벨: 지붕층
7576669 | 옥탑층 | 3850 | 5485.91 | 0.0987464 | 0.380174 | 21.1208 | 18.8108 | 0.338594 | 0 | -150 | yes | 옥탑층 | 3850 | 5485.91 | 18.8108 | 구속조건 - 상단 구속조건: 상위 레벨: 지붕층
7576670 | 옥탑층 | 3500 | 2582.01 | 0.0464762 | 0.162667 | 9.03703 | 5.25703 | 0.0946265 | 0 | -500 | no | 옥탑층 | 3500 | 2582.01 | 5.25703 | 구속조건 - 상단 구속조건: 상위 레벨: 지붕층
7577141 | 옥탑층 | 3850 | 5467.91 | 0.0984224 | 0.378926 | 21.0515 | 21.0515 | 0.378926 | 0 | -150 | yes | 옥탑층 | 3850 | 5485.91 | 21.0515 | 구속조건 - 상단 구속조건: 상위 레벨: 지붕층
7610431 | 지상 1층 | 3500 | 54.9823 | 0.000989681 | 0.00346389 | 0.192438 | 0.192438 | 0.00346389 | 80 | -1220 | no | 지상 1층 | 3500 | 63.9823 | 0.192438 | 구속조건 - 상단 구속조건: 상위 레벨: 지상 2층
7617369 | 지상 3층 | 2900 | 767.385 | 0.0138129 | 0.0400575 | 2.22542 | 2.22542 | 0.0400575 | 80 | 0 | no | 지상 3층 | 2900 | 758.385 | 2.22542
7617447 | 지상 3층 | 2900 | 750 | 0.0135 | 0.03915 | 2.175 | 2.175 | 0.03915 | 80 | 0 | no | 지상 3층 | 2900 | 759 | 2.175
7617723 | 지상 3층 | 2900 | 750 | 0.0135 | 0.03915 | 2.175 | 2.175 | 0.03915 | 80 | 0 | no | 지상 3층 | 2900 | 759 | 2.175
7617801 | 지상 3층 | 2900 | 768 | 0.013824 | 0.0400896 | 2.2272 | 2.2272 | 0.0400896 | 80 | 0 | no | 지상 3층 | 2900 | 768 | 2.2272
7617901 | 지상 3층 | 2900 | 817.983 | 0.0147237 | 0.0426987 | 2.37215 | 2.37215 | 0.0426987 | 80 | 0 | no | 지상 3층 | 2900 | 817.983 | 2.37215
7618230 | 지상 3층 | 2900 | 768 | 0.013824 | 0.0400896 | 2.2272 | 2.2272 | 0.0400896 | 80 | 0 | no | 지상 3층 | 2900 | 768 | 2.2272
7618231 | 지상 3층 | 2900 | 737.5 | 0.013275 | 0.0384975 | 2.13875 | 2.13875 | 0.0384975 | 80 | 0 | no | 지상 3층 | 2900 | 737.5 | 2.13875
7618338 | 지상 3층 | 2900 | 768 | 0.013824 | 0.0400896 | 2.2272 | 2.2272 | 0.0400896 | 80 | 0 | no | 지상 3층 | 2900 | 768 | 2.2272
7618339 | 지상 3층 | 2900 | 737.5 | 0.013275 | 0.0384975 | 2.13875 | 2.13875 | 0.0384975 | 80 | 0 | no | 지상 3층 | 2900 | 737.5 | 2.13875
7618454 | 지상 3층 | 2900 | 768 | 0.013824 | 0.0400896 | 2.2272 | 2.2272 | 0.0400896 | 80 | 0 | no | 지상 3층 | 2900 | 768 | 2.2272
7618546 | 지상 3층 | 2900 | 749.983 | 0.0134997 | 0.0391491 | 2.17495 | 2.17495 | 0.0391491 | 80 | 0 | no | 지상 3층 | 2900 | 749.983 | 2.17495
7709674 | 지상 2층 | 3100 | 818.017 | 0.0147243 | 0.0456454 | 2.53585 | 2.53585 | 0.0456454 | 80 | 0 | no | 지상 2층 | 3100 | 840.267 | 2.53585
7709676 | 지상 4층 | 2906 | 800 | 0.0144 | 0.0418464 | 2.3248 | 2.3248 | 0.0418464 | 80 | 0 | no | 지상 4층 | 2906 | 831.25 | 2.3248
7709678 | 지상 5층 | 2907 | 800.035 | 0.0144006 | 0.0418626 | 2.3257 | 2.3257 | 0.0418626 | 80 | 0 | no | 지상 5층 | 2907 | 831.285 | 2.3257
7709680 | 지상 6층 | 2907 | 800.035 | 0.0144006 | 0.0418626 | 2.3257 | 2.3257 | 0.0418626 | 80 | 0 | no | 지상 6층 | 2907 | 831.285 | 2.3257
7709682 | 지상 7층 | 2907 | 800.035 | 0.0144006 | 0.0418626 | 2.3257 | 2.3257 | 0.0418626 | 80 | 0 | no | 지상 7층 | 2907 | 831.285 | 2.3257
7709684 | 지상 8층 | 2600 | 700 | 0.0126 | 0.03276 | 1.82 | 1.82 | 0.03276 | 80 | 0 | no | 지상 8층 | 2600 | 731.25 | 1.82
7709686 | 지상 9층 | 3007 | 700.035 | 0.0126006 | 0.0378901 | 2.10501 | 2.10501 | 0.0378901 | 80 | 0 | no | 지상 9층 | 3007 | 731.285 | 2.10501
7710265 | 지상 3층 | 1000 | 6419.5 | 0.115551 | 0.115551 | 6.4195 | 6.4195 | 0.115551 | 2700 | -400 | no | 지상 3층 | 1000 | 6419.5 | 6.4195 | 구속조건 - 상단 구속조건: 상위 레벨: 지상 4층
7710708 | 지상 3층 | 1000 | 6600 | 0.1188 | 0.1188 | 6.6 | 6.6 | 0.1188 | 2700 | -400 | no | 지상 3층 | 1000 | 6591 | 6.6 | 구속조건 - 상단 구속조건: 상위 레벨: 지상 4층
7710887 | 지상 3층 | 1000 | 7164 | 0.128952 | 0.128952 | 7.164 | 7.164 | 0.128952 | 2700 | -400 | no | 지상 3층 | 1000 | 7182 | 7.164 | 구속조건 - 상단 구속조건: 상위 레벨: 지상 4층
7711380 | 지상 4층 | 3200 | 600 | 0.0108 | 0.03456 | 1.92 | 1.92 | 0.03456 | 80 | 0 | no | 지상 4층 | 3200 | 609 | 1.92
7711382 | 지상 5층 | 3200 | 600.025 | 0.0108005 | 0.0345615 | 1.92008 | 1.92008 | 0.0345615 | 80 | 0 | no | 지상 5층 | 3200 | 609.025 | 1.92008
7711384 | 지상 6층 | 3200 | 600 | 0.0108 | 0.03456 | 1.92 | 1.92 | 0.03456 | 80 | 0 | no | 지상 6층 | 3200 | 609 | 1.92
7711386 | 지상 7층 | 3200 | 600 | 0.0108 | 0.03456 | 1.92 | 1.92 | 0.03456 | 80 | 0 | no | 지상 7층 | 3200 | 609 | 1.92
7714911 | 지상 3층 | 700 | 15400 | 0.2772 | 0.19404 | 10.78 | 10.78 | 0.19404 | 80 | 0 | no | 지상 3층 | 4020 | 27091 | 10.78 | 구속조건 - 상단 구속조건: 상위 레벨: 지상 4층
7743669 | 지상 1층 | 30 | 1142.97 | 0.0205734 | 0.000617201 | 0.034289 | 0.034289 | 0.000617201 | 80 | -1170 | no | 지상 1층 | 3550 | 1187.97 | 0.034289 | 구속조건 - 상단 구속조건: 상위 레벨: 지상 2층
7745789 | 지상 1층 | 3500 | 9.97483 | 0.000179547 | 0.001134 | 0.063 | 0.063 | 0.000628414 | 80 | -1220 | no | 지상 1층 | 3500 | 9.97483 | 0.0349119 | 구속조건 - 상단 구속조건: 상위 레벨: 지상 2층
7747560 | 지상 1층 | 3500 | 3436.99 | 0.0618658 | 0.21653 | 12.0295 | 12.0295 | 0.21653 | 80 | -1220 | no | 지상 1층 | 3500 | 3490.99 | 12.0295 | 구속조건 - 상단 구속조건: 상위 레벨: 지상 2층
7751015 | 지상 1층 | 3550 | 36.9823 | 0.000665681 | 0.00236317 | 0.131287 | 0.131287 | 0.00236317 | 80 | -1170 | no | 지상 1층 | 3550 | 54.9823 | 0.131287 | 구속조건 - 상단 구속조건: 상위 레벨: 지상 2층
7756198 | 지상 2층 | 3100 | 674.739 | 0.0121453 | 0.0376504 | 2.09169 | 2.09169 | 0.0376504 | 80 | 0 | no | 지상 2층 | 3100 | 746.239 | 2.09169
7821767 | 지상 9층 | 2900 | 7400.02 | 0.1332 | 0.386281 | 21.4601 | 21.4601 | 0.386281 | 80 | 0 | no | 지상 9층 | 2900 | 7391.02 | 21.4601
7822169 | 지상 9층 | 2900 | 4832 | 0.086976 | 0.25223 | 14.0128 | 14.0128 | 0.25223 | 80 | 0 | no | 지상 9층 | 2900 | 4832 | 14.0128
7822344 | 지상 9층 | 2900 | 7663.99 | 0.137952 | 0.36604 | 20.3356 | 20.3356 | 0.36604 | 80 | 0 | no | 지상 9층 | 2900 | 7681.99 | 20.3356
7822629 | 지상 9층 | 2900 | 5050 | 0.0909 | 0.26361 | 14.645 | 14.645 | 0.26361 | 80 | 0 | no | 지상 9층 | 2900 | 5050 | 14.645
7822791 | 지상 9층 | 2900 | 5309.98 | 0.0955796 | 0.277181 | 15.3989 | 15.3989 | 0.277181 | 80 | 0 | no | 지상 9층 | 2900 | 5363.98 | 15.3989
8045171 | 지상 9층 | 2900 | 2582.64 | 0.0464875 | 0.134814 | 7.48966 | 7.48966 | 0.134814 | 0 | 0 | no | 지상 9층 | 2900 | 2582.64 | 7.48966
8045298 | 지상 9층 | 2900 | 5482 | 0.098676 | 0.28616 | 15.8978 | 15.8978 | 0.28616 | 0 | 0 | no | 지상 9층 | 2900 | 5482 | 15.8978
8045394 | 지상 9층 | 2900 | 2564.64 | 0.0461635 | 0.133874 | 7.43746 | 7.43746 | 0.133874 | 0 | 0 | no | 지상 9층 | 2900 | 2582.64 | 7.43746
8045455 | 지상 9층 | 4500 | 2582 | 0.046476 | 0.209142 | 11.619 | 11.619 | 0.209142 | 0 | 0 | no | 지상 9층 | 4500 | 2582 | 11.619 | 구속조건 - 상단 구속조건: 상위 레벨: 지상 10층
8045456 | 지상 9층 | 4500 | 5482 | 0.098676 | 0.444042 | 24.669 | 24.669 | 0.444042 | 0 | 0 | no | 지상 9층 | 4500 | 5482 | 24.669 | 구속조건 - 상단 구속조건: 상위 레벨: 지상 10층
8045457 | 지상 9층 | 4500 | 2582 | 0.046476 | 0.209142 | 11.619 | 7.839 | 0.141102 | 0 | 0 | no | 지상 9층 | 4500 | 2582 | 7.839 | 구속조건 - 상단 구속조건: 상위 레벨: 지상 10층
8045458 | 지상 9층 | 4500 | 5482 | 0.098676 | 0.444042 | 24.669 | 24.669 | 0.444042 | 0 | 0 | no | 지상 9층 | 4500 | 5482 | 24.669 | 구속조건 - 상단 구속조건: 상위 레벨: 지상 10층
8055074 | 지상 10층 | 5000 | 2573.99 | 0.0463318 | 0.231659 | 12.87 | 12.87 | 0.231659 | 0 | 0 | no | 지상 10층 | 5000 | 2691.99 | 12.87 | 구속조건 - 상단 구속조건: 상위 레벨: 옥탑층

# IfcWallStandardCase: 기본 벽:A1-32-07A-콘크리트면정리, 바닥방수연장, 시멘트모르타르(미장용), 수성페인트(내부) (24mm) (75)
Type - PredefinedType: STANDARD; Material: WA611-수성페인트 (내부) 벽 (3회) 1 mm, WA551-시멘트모르타르 (내부) 벽 24mm 21 mm, WA961-바닥방수 연장 1 mm, WA555-콘크리트면정리 벽 (내부) 1 mm
Type - ID 데이터 - 단가: 0; 유형 이름: A1-32-07A-콘크리트면정리, 바닥방수연장, 시멘트모르타르(미장용), 수성페인트(내부) (24mm)
Type - 그래픽 - 거친 축척 채우기 색상: 0
Type - 기타 - 카테고리: 벽; KBIMS-부위코드: E24; 불연성재료: 불연재료; 조달청표준공사코드: ANC132110000+AGA114600000+AHG3+AGA441100000; 패밀리 이름: 기본 벽
Type - 시공 - 기능: 외부; 끝단부 마무리: 없음; 인서트 부위 마무리: 마무리하지 않음; 폭: 24 mm
Type - 해석 특성 - 거칠기: 1; 열 저항(R): 0.035006; 열 전달 계수(U): 28.5665 kg/K/s3; 열 질량: 37.8109; 흡수율: 30.48
Type - Pset_WallCommon - IsExternal: yes; ThermalTransmittance: 28.5665 kg/K/s3
BaseQuantities - Width: 24 mm
공정 - 생성 공정: 새 구성
구속조건 - 매스와 관련됨: no; 룸 경계: yes; 베이스 확장 거리: 0 mm; 벽 베이스가 부착됩니다.: no; 상단 간격띄우기: 0 mm; 상단 확장 거리: 0 mm; 상단이 부착됩니다.: no
기타 - 패밀리: 기본 벽; 유형: A1-32-07A-콘크리트면정리, 바닥방수연장, 시멘트모르타르(미장용), 수성페인트(내부) (24mm); 유형 ID: 6825625; 패밀리 및 유형: 기본 벽: A1-32-07A-콘크리트면정리, 바닥방수연장, 시멘트모르타르(미장용), 수성페인트(내부) (24mm)
단면형상 정의 - 단면형상: 수직
Pset_QuantityTakeOff - Reference: A1-32-07A-콘크리트면정리, 바닥방수연장, 시멘트모르타르(미장용), 수성페인트(내부) (24mm); sets with these values: 2
Pset_WallCommon - ExtendToStructure: no; Reference: A1-32-07A-콘크리트면정리, 바닥방수연장, 시멘트모르타르(미장용), 수성페인트(내부) (24mm)
Name (기본 벽:A1-32-07A-콘크리트면정리, 바닥방수연장, 시멘트모르타르(미장용), 수성페인트(내부) (24mm):...) | In | Height (mm) = 미연결 높이 (mm) | Length (mm) | GrossFootprintArea (m2) | GrossVolume (m3) | GrossSideArea (m2) | NetSideArea (m2) = 면적 (m2) | NetVolume (m3) = 체적 (m3) | 베이스 구속조건 | 위치선 | 베이스 간격띄우기 (mm) | 구조 = LoadBearing | 구조적 용도 | 길이 (mm)
7557818 | 지상 3층 | 2600 | 2500.01 | 0.0600002 | 0.110641 | 4.61002 | 4.61002 | 0.110641 | 지상 3층 | 마감면:내부 | 80 | no | 비교좌장치 | 2588.01
7557823 | 지상 3층 | 2600 | 11295 | 0.271081 | 0.65441 | 27.2671 | 26.8771 | 0.64505 | 지상 3층 | 마감면:내부 | 80 | no | 비교좌장치 | 11407
7557826 | 지상 3층 | 2600 | 523.991 | 0.0125758 | 0.0326971 | 1.36238 | 1.36238 | 0.0326971 | 지상 3층 | 마감면:내부 | 80 | no | 비교좌장치 | 611.991
7557827 | 지상 3층 | 2600 | 6699.91 | 0.160798 | 0.393114 | 16.3798 | 16.3798 | 0.393114 | 지상 3층 | 마감면:내부 | 80 | no | 비교좌장치 | 6699.91
7557828 | 지상 3층 | 2600 | 5923.75 | 0.14217 | 0.235002 | 9.79174 | 9.79174 | 0.235002 | 지상 3층 | 마감면:내부 | 80 | no | 비교좌장치 | 5923.75
7557829 | 지상 3층 | 2600 | 14949.9 | 0.358798 | 0.807114 | 33.6298 | 33.6298 | 0.807114 | 지상 3층 | 마감면:내부 | 80 | no | 비교좌장치 | 15061.9
7559408 | 지상 3층 | 2900 | 7637.25 | 0.183294 | 0.531553 | 22.148 | 22.148 | 0.531553 | 지상 3층 | 마감면:내부 | 80 | no | 비교좌장치 | 7637.25
7561301 | 지상 4층 | 2600 | 12133.9 | 0.291214 | 0.631396 | 26.3082 | 26.3082 | 0.631396 | 지상 4층 | 마감면:외부 | 80 | no | 비교좌장치 | 12166.9
7561302 | 지상 4층 | 2600 | 5924.01 | 0.142176 | 0.236602 | 9.85842 | 9.85842 | 0.236602 | 지상 4층 | 구조체 면:외부 | 0 | yes | 교좌장치 | 5924.01 | ID 데이터 - 연관 있음: no; 구조 - 보강 철근 피복 - 다른 면: 보강 철근 피복 1 <25 mm>; 보강 철근 피복 - 내부 면: 보강 철근 피복 1 <25 mm>; 보강 철근 피복 - 외부 면: 보강 철근 피복 1 <25 mm>
7561303 | 지상 4층 | 2600 | 6699.91 | 0.160798 | 0.418074 | 17.4198 | 16.3798 | 0.393114 | 지상 4층 | 마감면:내부 | 0 | no | 비교좌장치 | 6699.91
7561304 | 지상 4층 | 2600 | 3024 | 0.072576 | 0.0979776 | 4.0824 | 4.0824 | 0.0979776 | 지상 4층 | 마감면:내부 | 80 | no | 비교좌장치 | 3012
7561305 | 지상 4층 | 2600 | 11300 | 0.271201 | 0.654722 | 27.2801 | 26.8901 | 0.645362 | 지상 4층 | 마감면:내부 | 80 | no | 비교좌장치 | 11412
7561307 | 지상 4층 | 2600 | 4600 | 0.1104 | 0.23664 | 9.86 | 9.86 | 0.23664 | 지상 4층 | 마감면:내부 | 80 | no | 비교좌장치 | 4600
7561308 | 지상 4층 | 2600 | 475.991 | 0.0114238 | 0.0297019 | 1.23758 | 1.23758 | 0.0297019 | 지상 4층 | 마감면:내부 | 80 | no | 비교좌장치 | 499.991
7561309 | 지상 4층 | 2600 | 800 | 0.0192 | 0.04992 | 2.08 | 2.08 | 0.04992 | 지상 4층 | 마감면:내부 | 80 | no | 비교좌장치 | 800
7561310 | 지상 4층 | 2600 | 655 | 0.01572 | 0.040872 | 1.703 | 1.703 | 0.040872 | 지상 4층 | 마감면:내부 | 80 | no | 비교좌장치 | 655
7561311 | 지상 4층 | 2600 | 800 | 0.0192 | 0.04992 | 2.08 | 2.08 | 0.04992 | 지상 4층 | 마감면:내부 | 80 | no | 비교좌장치 | 800
7561312 | 지상 4층 | 2600 | 800 | 0.0192 | 0.04992 | 2.08 | 2.08 | 0.04992 | 지상 4층 | 마감면:내부 | 80 | no | 비교좌장치 | 800
7562707 | 지상 5층 | 2600 | 12137.9 | 0.29131 | 0.631646 | 26.3186 | 26.3186 | 0.631646 | 지상 5층 | 마감면:외부 | 80 | no | 비교좌장치 | 12170.9
7562708 | 지상 5층 | 2680 | 5924.01 | 0.142176 | 0.381032 | 15.8763 | 10.2663 | 0.246392 | 지상 5층 | 구조체 면:외부 | 0 | yes | 교좌장치 | 5924.01 | ID 데이터 - 연관 있음: no; 구조 - 보강 철근 피복 - 다른 면: 보강 철근 피복 1 <25 mm>; 보강 철근 피복 - 내부 면: 보강 철근 피복 1 <25 mm>; 보강 철근 피복 - 외부 면: 보강 철근 피복 1 <25 mm>
7562709 | 지상 5층 | 2680 | 6703.91 | 0.160894 | 0.431195 | 17.9665 | 16.9265 | 0.406235 | 지상 5층 | 마감면:내부 | 0 | no | 비교좌장치 | 6703.91
7562710 | 지상 5층 | 2600 | 3024 | 0.072576 | 0.0979776 | 4.0824 | 4.0824 | 0.0979776 | 지상 5층 | 마감면:내부 | 80 | no | 비교좌장치 | 3012
7562711 | 지상 5층 | 2600 | 11300 | 0.271201 | 0.654722 | 27.2801 | 26.8901 | 0.645362 | 지상 5층 | 마감면:내부 | 80 | no | 비교좌장치 | 11412
7562713 | 지상 5층 | 2600 | 4600 | 0.1104 | 0.23664 | 9.86 | 9.86 | 0.23664 | 지상 5층 | 마감면:내부 | 80 | no | 비교좌장치 | 4600
7562714 | 지상 5층 | 2600 | 475.991 | 0.0114238 | 0.0297019 | 1.23758 | 1.23758 | 0.0297019 | 지상 5층 | 마감면:내부 | 80 | no | 비교좌장치 | 499.991
7562715 | 지상 5층 | 2600 | 800 | 0.0192 | 0.04992 | 2.08 | 2.08 | 0.04992 | 지상 5층 | 마감면:내부 | 80 | no | 비교좌장치 | 800
7562716 | 지상 5층 | 2600 | 710 | 0.01704 | 0.044304 | 1.846 | 1.846 | 0.044304 | 지상 5층 | 마감면:내부 | 80 | no | 비교좌장치 | 755
7562717 | 지상 5층 | 2900 | 799.982 | 0.0191996 | 0.0556787 | 2.31995 | 2.31995 | 0.0556787 | 지상 5층 | 마감면:내부 | 80 | no | 비교좌장치 | 799.982
7562718 | 지상 5층 | 2900 | 800.021 | 0.0192005 | 0.0556815 | 2.32006 | 2.32006 | 0.0556815 | 지상 5층 | 마감면:내부 | 80 | no | 비교좌장치 | 800.021
7563884 | 지상 6층 | 2600 | 12137.9 | 0.29131 | 0.631646 | 26.3186 | 26.3186 | 0.631646 | 지상 6층 | 마감면:외부 | 80 | no | 비교좌장치 | 12170.9
7563885 | 지상 6층 | 2600 | 5924.01 | 0.142176 | 0.236602 | 9.85842 | 9.85842 | 0.236602 | 지상 6층 | 구조체 면:외부 | 0 | yes | 교좌장치 | 5924.01 | ID 데이터 - 연관 있음: no; 구조 - 보강 철근 피복 - 다른 면: 보강 철근 피복 1 <25 mm>; 보강 철근 피복 - 내부 면: 보강 철근 피복 1 <25 mm>; 보강 철근 피복 - 외부 면: 보강 철근 피복 1 <25 mm>
7563886 | 지상 6층 | 2600 | 6703.91 | 0.160894 | 0.418324 | 17.4302 | 16.3902 | 0.393364 | 지상 6층 | 마감면:내부 | 0 | no | 비교좌장치 | 6703.91
7563887 | 지상 6층 | 2600 | 3024 | 0.072576 | 0.0979776 | 4.0824 | 4.0824 | 0.0979776 | 지상 6층 | 마감면:내부 | 80 | no | 비교좌장치 | 3012
7563888 | 지상 6층 | 2600 | 11300 | 0.271201 | 0.654722 | 27.2801 | 26.8901 | 0.645362 | 지상 6층 | 마감면:내부 | 80 | no | 비교좌장치 | 11412
7563890 | 지상 6층 | 2600 | 4600 | 0.1104 | 0.23664 | 9.86 | 9.86 | 0.23664 | 지상 6층 | 마감면:내부 | 80 | no | 비교좌장치 | 4600
7563891 | 지상 6층 | 2600 | 475.991 | 0.0114238 | 0.0297019 | 1.23758 | 1.23758 | 0.0297019 | 지상 6층 | 마감면:내부 | 80 | no | 비교좌장치 | 499.991
7563892 | 지상 6층 | 2600 | 802.517 | 0.0192604 | 0.0500771 | 2.08655 | 2.08655 | 0.0500771 | 지상 6층 | 마감면:내부 | 80 | no | 비교좌장치 | 802.517
7563893 | 지상 6층 | 2600 | 710 | 0.01704 | 0.044304 | 1.846 | 1.846 | 0.044304 | 지상 6층 | 마감면:내부 | 80 | no | 비교좌장치 | 755
7563894 | 지상 6층 | 2600 | 800.017 | 0.0192004 | 0.0499211 | 2.08005 | 2.08005 | 0.0499211 | 지상 6층 | 마감면:내부 | 80 | no | 비교좌장치 | 800.017
7563895 | 지상 6층 | 2600 | 799.985 | 0.0191996 | 0.0499191 | 2.07996 | 2.07996 | 0.0499191 | 지상 6층 | 마감면:내부 | 80 | no | 비교좌장치 | 799.985
7563897 | 지상 7층 | 2600 | 12137.9 | 0.29131 | 0.631646 | 26.3186 | 26.3186 | 0.631646 | 지상 7층 | 마감면:외부 | 80 | no | 비교좌장치 | 12170.9
7563898 | 지상 7층 | 2600 | 5924.01 | 0.142176 | 0.236602 | 9.85842 | 9.85842 | 0.236602 | 지상 7층 | 구조체 면:외부 | 0 | yes | 교좌장치 | 5924.01 | ID 데이터 - 연관 있음: no; 구조 - 보강 철근 피복 - 다른 면: 보강 철근 피복 1 <25 mm>; 보강 철근 피복 - 내부 면: 보강 철근 피복 1 <25 mm>; 보강 철근 피복 - 외부 면: 보강 철근 피복 1 <25 mm>
7563900 | 지상 7층 | 2600 | 3024 | 0.072576 | 0.0979776 | 4.0824 | 4.0824 | 0.0979776 | 지상 7층 | 마감면:내부 | 80 | no | 비교좌장치 | 3012
7563901 | 지상 7층 | 2600 | 11300 | 0.2712 | 0.65472 | 27.28 | 26.89 | 0.64536 | 지상 7층 | 마감면:내부 | 80 | no | 비교좌장치 | 11412
7563903 | 지상 7층 | 2600 | 4600 | 0.1104 | 0.23664 | 9.86 | 9.86 | 0.23664 | 지상 7층 | 마감면:내부 | 80 | no | 비교좌장치 | 4600
7563904 | 지상 7층 | 2600 | 499.991 | 0.0119998 | 0.0311995 | 1.29998 | 1.29998 | 0.0311995 | 지상 7층 | 마감면:내부 | 80 | no | 비교좌장치 | 499.991
7563905 | 지상 7층 | 2600 | 802.517 | 0.0192604 | 0.0500771 | 2.08655 | 2.08655 | 0.0500771 | 지상 7층 | 마감면:내부 | 80 | no | 비교좌장치 | 802.517
7563906 | 지상 7층 | 2600 | 710 | 0.01704 | 0.044304 | 1.846 | 1.846 | 0.044304 | 지상 7층 | 마감면:내부 | 80 | no | 비교좌장치 | 755
7563907 | 지상 7층 | 2600 | 800 | 0.0192 | 0.04992 | 2.08 | 2.08 | 0.04992 | 지상 7층 | 마감면:내부 | 80 | no | 비교좌장치 | 800
7563908 | 지상 7층 | 2600 | 800.021 | 0.0192005 | 0.0499213 | 2.08005 | 2.08005 | 0.0499213 | 지상 7층 | 마감면:내부 | 80 | no | 비교좌장치 | 800.021
7563910 | 지상 8층 | 2600 | 12137.9 | 0.29131 | 0.631646 | 26.3186 | 26.3186 | 0.631646 | 지상 8층 | 마감면:외부 | 80 | no | 비교좌장치 | 12170.9
7563911 | 지상 8층 | 2600 | 5924.01 | 0.142176 | 0.236602 | 9.85842 | 9.85842 | 0.236602 | 지상 8층 | 구조체 면:외부 | 0 | yes | 교좌장치 | 5924.01 | ID 데이터 - 연관 있음: no; 구조 - 보강 철근 피복 - 다른 면: 보강 철근 피복 1 <25 mm>; 보강 철근 피복 - 내부 면: 보강 철근 피복 1 <25 mm>; 보강 철근 피복 - 외부 면: 보강 철근 피복 1 <25 mm>
7563913 | 지상 8층 | 2600 | 3024 | 0.072576 | 0.0979776 | 4.0824 | 4.0824 | 0.0979776 | 지상 8층 | 마감면:내부 | 80 | no | 비교좌장치 | 3012
7563914 | 지상 8층 | 2600 | 11300 | 0.2712 | 0.65472 | 27.28 | 27.28 | 0.65472 | 지상 8층 | 마감면:내부 | 80 | no | 비교좌장치 | 11412
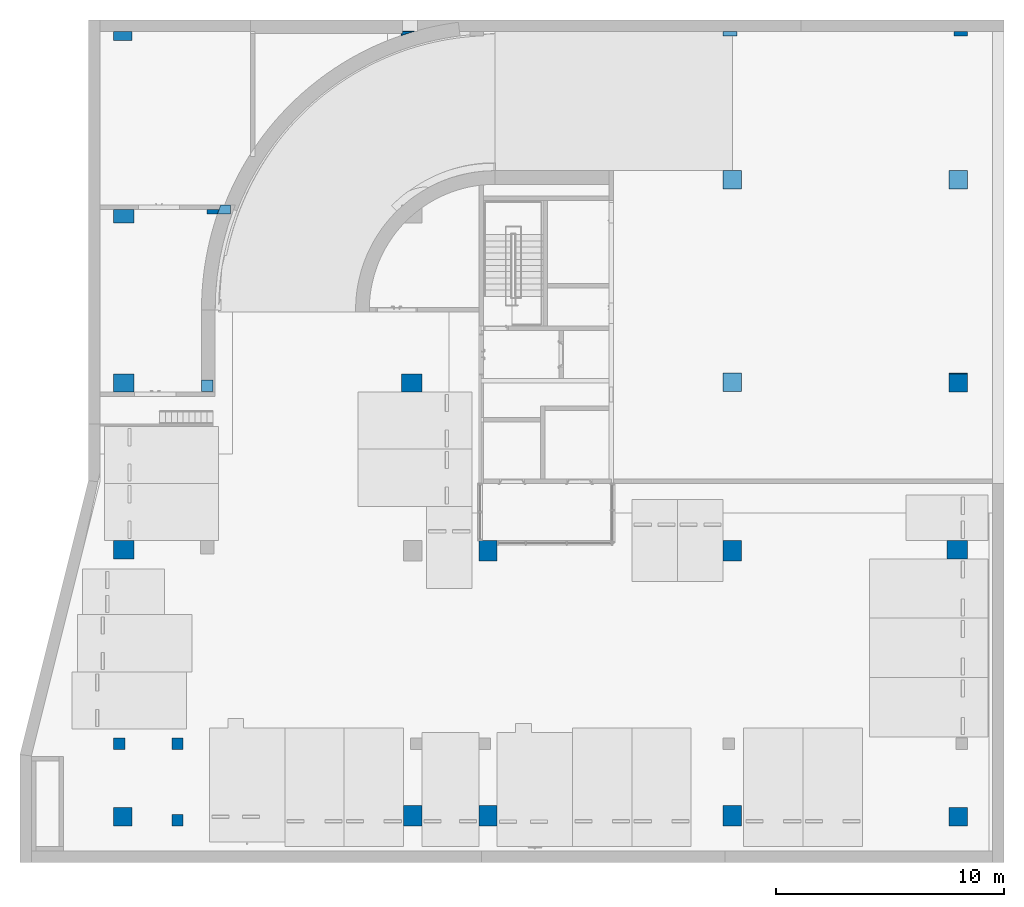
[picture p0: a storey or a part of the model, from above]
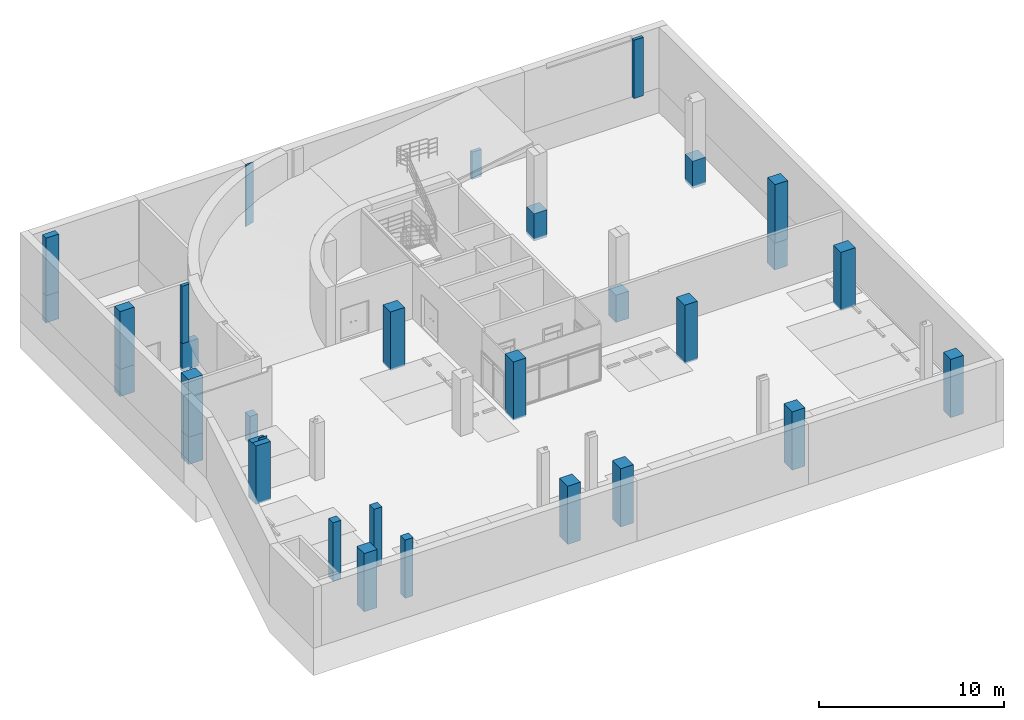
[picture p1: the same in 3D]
Properties of the parts of a building model (IFC2X3), part 37 of 39

# IfcWallStandardCase: 기본 벽:A1-32-07A-콘크리트면정리, 바닥방수연장, 시멘트모르타르(미장용), 수성페인트(내부) (24mm) (75)
Name (기본 벽:A1-32-07A-콘크리트면정리, 바닥방수연장, 시멘트모르타르(미장용), 수성페인트(내부) (24mm):...) | In | Height (mm) = 미연결 높이 (mm) | Length (mm) | GrossFootprintArea (m2) | GrossVolume (m3) | GrossSideArea (m2) | NetSideArea (m2) = 면적 (m2) | NetVolume (m3) = 체적 (m3) | 베이스 구속조건 | 위치선 | 베이스 간격띄우기 (mm) | 구조 = LoadBearing | 구조적 용도 | 길이 (mm)
7563916 | 지상 8층 | 2600 | 4600 | 0.1104 | 0.23664 | 9.86 | 9.86 | 0.23664 | 지상 8층 | 마감면:내부 | 80 | no | 비교좌장치 | 4600
7563917 | 지상 8층 | 2600 | 499.991 | 0.0119998 | 0.0311995 | 1.29998 | 1.29998 | 0.0311995 | 지상 8층 | 마감면:내부 | 80 | no | 비교좌장치 | 499.991
7563918 | 지상 8층 | 2600 | 802.517 | 0.0192604 | 0.0500771 | 2.08655 | 2.08655 | 0.0500771 | 지상 8층 | 마감면:내부 | 80 | no | 비교좌장치 | 802.517
7563919 | 지상 8층 | 2600 | 610.035 | 0.0146408 | 0.0380662 | 1.58609 | 1.58609 | 0.0380662 | 지상 8층 | 마감면:내부 | 80 | no | 비교좌장치 | 655.035
7563920 | 지상 8층 | 2600 | 700 | 0.0168 | 0.04368 | 1.82 | 1.82 | 0.04368 | 지상 8층 | 마감면:내부 | 80 | no | 비교좌장치 | 700
7563921 | 지상 8층 | 2600 | 699.983 | 0.0167996 | 0.0436789 | 1.81995 | 1.81995 | 0.0436789 | 지상 8층 | 마감면:내부 | 80 | no | 비교좌장치 | 699.983
7563923 | 지상 9층 | 2900 | 14977.9 | 0.35947 | 0.916702 | 38.1959 | 38.1959 | 0.916702 | 지상 9층 | 마감면:외부 | 80 | no | 비교좌장치 | 15065.9
7563924 | 지상 9층 | 2900 | 5924.01 | 0.142176 | 0.412311 | 17.1796 | 11.5696 | 0.277671 | 지상 9층 | 구조체 면:외부 | 0 | yes | 교좌장치 | 5924.01 | ID 데이터 - 연관 있음: no; 구조 - 보강 철근 피복 - 다른 면: 보강 철근 피복 1 <25 mm>; 보강 철근 피복 - 내부 면: 보강 철근 피복 1 <25 mm>; 보강 철근 피복 - 외부 면: 보강 철근 피복 1 <25 mm>
7563926 | 지상 9층 | 2900 | 3024 | 0.072576 | 0.11975 | 4.9896 | 4.9896 | 0.11975 | 지상 9층 | 마감면:내부 | 80 | no | 비교좌장치 | 3012
7563927 | 지상 9층 | 2900 | 11300 | 0.2712 | 0.73608 | 30.67 | 30.28 | 0.72672 | 지상 9층 | 마감면:내부 | 80 | no | 비교좌장치 | 11412
7563929 | 지상 9층 | 2900 | 4600 | 0.1104 | 0.26976 | 11.24 | 11.24 | 0.26976 | 지상 9층 | 마감면:내부 | 80 | no | 비교좌장치 | 4600
7563930 | 지상 9층 | 2900 | 499.991 | 0.0119998 | 0.0347994 | 1.44997 | 1.44997 | 0.0347994 | 지상 9층 | 마감면:내부 | 80 | no | 비교좌장치 | 499.991
7563931 | 지상 9층 | 2900 | 700 | 0.0168 | 0.04872 | 2.03 | 2.03 | 0.04872 | 지상 9층 | 마감면:내부 | 80 | no | 비교좌장치 | 700
7563932 | 지상 9층 | 2900 | 700 | 0.0168 | 0.04872 | 2.03 | 2.03 | 0.04872 | 지상 9층 | 마감면:내부 | 80 | no | 비교좌장치 | 700
7563933 | 지상 9층 | 2900 | 700.018 | 0.0168004 | 0.0487213 | 2.03005 | 2.03005 | 0.0487213 | 지상 9층 | 마감면:내부 | 80 | no | 비교좌장치 | 700.018
7563934 | 지상 9층 | 2900 | 700.021 | 0.0168005 | 0.0487215 | 2.03006 | 2.03006 | 0.0487215 | 지상 9층 | 마감면:내부 | 80 | no | 비교좌장치 | 700.021
7564692 | 지상 7층 | 2600 | 6679.91 | 0.160318 | 0.416826 | 17.3678 | 16.3278 | 0.391866 | 지상 7층 | 마감면:내부 | 0 | no | 비교좌장치 | 6703.91
7564823 | 지상 8층 | 2600 | 6679.91 | 0.160318 | 0.416826 | 17.3678 | 16.3278 | 0.391866 | 지상 8층 | 마감면:내부 | 0 | no | 비교좌장치 | 6703.91
7564825 | 지상 9층 | 2900 | 6679.91 | 0.160318 | 0.464922 | 19.3717 | 18.3317 | 0.439962 | 지상 9층 | 마감면:내부 | 0 | no | 비교좌장치 | 6703.91
7697856 | 지상 9층 | 3200 | 2500.01 | 0.0600003 | 0.146641 | 6.11004 | 6.11004 | 0.146641 | 지상 9층 | 마감면:내부 | 80 | no | 비교좌장치 | 2645.01
7727693 | 지상 3층 | 2600 | 4576 | 0.109824 | 0.235142 | 9.7976 | 9.7976 | 0.235142 | 지상 3층 | 마감면:내부 | 80 | no | 비교좌장치 | 4600

# IfcWallStandardCase: 기본 벽:A1-33-01B-시멘트 모르타르, 도기질타일 (30mm) (116)
Type - PredefinedType: STANDARD; Material: WA352-도기질타일 벽 200x200 8 mm, WA551-시멘트모르타르 (내부) 벽 22mm 22 mm
Type - ID 데이터 - 단가: 0; 유형 이름: A1-33-01B-시멘트 모르타르, 도기질타일 (30mm)
Type - 그래픽 - 거친 축척 채우기 색상: 0
Type - 기타 - 카테고리: 벽; KBIMS-부위코드: E24; 불연성재료: 불연재료; 조달청표준공사코드: AMA112C+AGA114400000; 패밀리 이름: 기본 벽
Type - 시공 - 기능: 외부; 끝단부 마무리: 없음; 인서트 부위 마무리: 마무리하지 않음; 폭: 30 mm
Type - 해석 특성 - 거칠기: 1; 열 저항(R): 0.0305556; 열 전달 계수(U): 32.7273 kg/K/s3; 열 질량: 33.396; 흡수율: 30.48
Type - Pset_WallCommon - IsExternal: yes; ThermalTransmittance: 32.7273 kg/K/s3
BaseQuantities - Width: 30 mm
공정 - 생성 공정: 새 구성
구속조건 - 매스와 관련됨: no; 룸 경계: yes; 베이스 확장 거리: 0 mm; 벽 베이스가 부착됩니다.: no; 상단 확장 거리: 0 mm; 상단이 부착됩니다.: no; 위치선: 마감면:내부
구조 - 구조: no; 구조적 용도: 비교좌장치
기타 - 패밀리: 기본 벽; 유형: A1-33-01B-시멘트 모르타르, 도기질타일 (30mm); 유형 ID: 6831423; 패밀리 및 유형: 기본 벽: A1-33-01B-시멘트 모르타르, 도기질타일 (30mm)
단면형상 정의 - 단면형상: 수직
Pset_QuantityTakeOff - Reference: A1-33-01B-시멘트 모르타르, 도기질타일 (30mm); sets with these values: 2
Pset_WallCommon - LoadBearing: no; ExtendToStructure: no; Reference: A1-33-01B-시멘트 모르타르, 도기질타일 (30mm)
Name (기본 벽:A1-33-01B-시멘트 모르타르, 도기질타일 (30mm):...) | In | Height (mm) = 미연결 높이 (mm) | Length (mm) | GrossFootprintArea (m2) | GrossVolume (m3) | GrossSideArea (m2) | NetSideArea (m2) = 면적 (m2) | NetVolume (m3) = 체적 (m3) | 해설 | 상단 구속조건 | 베이스 구속조건 | 베이스 간격띄우기 (mm) | 상단 간격띄우기 (mm) | 길이 (mm)
7573899 | 지상 1층 | 2200 | 5500 | 0.165 | 0.363 | 12.1 | 12.1 | 0.363 | A | 상위 레벨: 지상 1층 | 지상 1층 | -500 | 1700 | 5470
7573900 | 지상 1층 | 2200 | 4399.93 | 0.131998 | 0.290396 | 9.67986 | 9.67986 | 0.290396 | A | 상위 레벨: 지상 1층 | 지상 1층 | -500 | 1700 | 4369.93
7573901 | 지상 1층 | 2200 | 2690 | 0.0807 | 0.17754 | 5.918 | 5.918 | 0.17754 | A | 상위 레벨: 지상 1층 | 지상 1층 | -500 | 1700 | 2720
7573902 | 지상 1층 | 2200 | 3139.98 | 0.0941995 | 0.207239 | 6.90796 | 5.94796 | 0.178439 | A | 상위 레벨: 지상 1층 | 지상 1층 | -500 | 1700 | 3169.98
7573904 | 지상 1층 | 2200 | 2540 | 0.0762 | 0.16764 | 5.588 | 5.588 | 0.16764 | A | 상위 레벨: 지상 1층 | 지상 1층 | -500 | 1700 | 2570
7573905 | 지상 1층 | 2200 | 2540 | 0.0762 | 0.16764 | 5.588 | 5.198 | 0.15594 | A | 상위 레벨: 지상 1층 | 지상 1층 | -500 | 1700 | 2570
7573906 | 지상 1층 | 2200 | 3169.98 | 0.0950995 | 0.209219 | 6.97396 | 6.97396 | 0.209219 | A | 상위 레벨: 지상 1층 | 지상 1층 | -500 | 1700 | 3169.98
7573908 | 지상 1층 | 2200 | 4400 | 0.132 | 0.2904 | 9.68 | 7.58 | 0.2274 | A | 상위 레벨: 지상 1층 | 지상 1층 | -500 | 1700 | 4385
7701287 | 지상 1층 | 2200 | 1414.98 | 0.0424495 | 0.0933888 | 3.11296 | 3.11296 | 0.0933888 |  | 상위 레벨: 지상 1층 | 지상 1층 | -500 | 1700 | 1429.98
7704854 | 지상 1층 | 2200 | 1414.98 | 0.0424495 | 0.0933888 | 3.11296 | 3.11296 | 0.0933888 |  | 상위 레벨: 지상 1층 | 지상 1층 | -500 | 1700 | 1429.98
7705099 | 지상 1층 | 2200 | 769.983 | 0.0230995 | 0.0508188 | 1.69396 | 1.69396 | 0.0508188 |  | 상위 레벨: 지상 1층 | 지상 1층 | -500 | 1700 | 784.983
7705128 | 지상 1층 | 2200 | 799.983 | 0.0239995 | 0.0527988 | 1.75996 | 1.75996 | 0.0527988 |  | 상위 레벨: 지상 1층 | 지상 1층 | -500 | 1700 | 784.983
7705230 | 지상 2층 | 2650 | 5500 | 0.165 | 0.43725 | 14.575 | 14.575 | 0.43725 | A | 상위 레벨: 지상 2층 | 지상 2층 | 40 | 2690 | 5470
7705231 | 지상 2층 | 2650 | 2690 | 0.0807 | 0.213855 | 7.1285 | 5.0285 | 0.150855 | A | 상위 레벨: 지상 2층 | 지상 2층 | 40 | 2690 | 2720
7705232 | 지상 2층 | 2650 | 3139.98 | 0.0941995 | 0.249629 | 8.32095 | 7.36095 | 0.220829 | A | 상위 레벨: 지상 2층 | 지상 2층 | 40 | 2690 | 3169.98
7705233 | 지상 2층 | 2650 | 3169.98 | 0.0950995 | 0.252014 | 8.40045 | 8.40045 | 0.252014 | A | 상위 레벨: 지상 2층 | 지상 2층 | 40 | 2690 | 3169.98
7705234 | 지상 2층 | 2650 | 1414.98 | 0.0424495 | 0.112491 | 3.7497 | 3.7497 | 0.112491 |  | 상위 레벨: 지상 2층 | 지상 2층 | 40 | 2690 | 1429.98
7705235 | 지상 2층 | 2650 | 1414.98 | 0.0424495 | 0.112491 | 3.7497 | 3.7497 | 0.112491 |  | 상위 레벨: 지상 2층 | 지상 2층 | 40 | 2690 | 1429.98
7705236 | 지상 2층 | 2650 | 799.983 | 0.0239995 | 0.0635986 | 2.11995 | 2.11995 | 0.0635986 |  | 상위 레벨: 지상 2층 | 지상 2층 | 40 | 2690 | 784.983
7705237 | 지상 2층 | 2650 | 799.983 | 0.0239995 | 0.0635986 | 2.11995 | 2.11995 | 0.0635986 |  | 상위 레벨: 지상 2층 | 지상 2층 | 40 | 2690 | 784.983
7705526 | 지상 3층 | 2650 | 5500 | 0.165 | 0.43725 | 14.575 | 14.575 | 0.43725 | A | 상위 레벨: 지상 3층 | 지상 3층 | 40 | 2690 | 5470
7705527 | 지상 3층 | 2650 | 2690 | 0.0807 | 0.213855 | 7.1285 | 5.0285 | 0.150855 | A | 상위 레벨: 지상 3층 | 지상 3층 | 40 | 2690 | 2720
7705528 | 지상 3층 | 2650 | 3139.98 | 0.0941995 | 0.249629 | 8.32095 | 7.36095 | 0.220829 | A | 상위 레벨: 지상 3층 | 지상 3층 | 40 | 2690 | 3169.98
7705529 | 지상 3층 | 2650 | 3169.98 | 0.0950995 | 0.252014 | 8.40045 | 8.40045 | 0.252014 | A | 상위 레벨: 지상 3층 | 지상 3층 | 40 | 2690 | 3169.98
7705530 | 지상 3층 | 2650 | 1414.98 | 0.0424495 | 0.112491 | 3.7497 | 3.7497 | 0.112491 |  | 상위 레벨: 지상 3층 | 지상 3층 | 40 | 2690 | 1429.98
7705531 | 지상 3층 | 2650 | 1414.98 | 0.0424495 | 0.112491 | 3.7497 | 3.7497 | 0.112491 |  | 상위 레벨: 지상 3층 | 지상 3층 | 40 | 2690 | 1429.98
7705532 | 지상 3층 | 2650 | 769.983 | 0.0230995 | 0.0612136 | 2.04045 | 2.04045 | 0.0612136 |  | 상위 레벨: 지상 3층 | 지상 3층 | 40 | 2690 | 784.983
7705533 | 지상 3층 | 2650 | 799.983 | 0.0239995 | 0.0635986 | 2.11995 | 2.11995 | 0.0635986 |  | 상위 레벨: 지상 3층 | 지상 3층 | 40 | 2690 | 784.983
7705535 | 지상 4층 | 2650 | 5500 | 0.165 | 0.43725 | 14.575 | 14.575 | 0.43725 | A | 상위 레벨: 지상 4층 | 지상 4층 | 40 | 2690 | 5470
7705536 | 지상 4층 | 2650 | 2690 | 0.0807 | 0.213855 | 7.1285 | 5.0285 | 0.150855 | A | 상위 레벨: 지상 4층 | 지상 4층 | 40 | 2690 | 2720
7705537 | 지상 4층 | 2650 | 3139.98 | 0.0941995 | 0.249629 | 8.32095 | 7.36095 | 0.220829 | A | 상위 레벨: 지상 4층 | 지상 4층 | 40 | 2690 | 3169.98
7705538 | 지상 4층 | 2650 | 3169.98 | 0.0950995 | 0.252014 | 8.40045 | 8.40045 | 0.252014 | A | 상위 레벨: 지상 4층 | 지상 4층 | 40 | 2690 | 3169.98
7705539 | 지상 4층 | 2650 | 1414.98 | 0.0424495 | 0.112491 | 3.7497 | 3.7497 | 0.112491 |  | 상위 레벨: 지상 4층 | 지상 4층 | 40 | 2690 | 1429.98
7705540 | 지상 4층 | 2650 | 1414.98 | 0.0424495 | 0.112491 | 3.7497 | 3.7497 | 0.112491 |  | 상위 레벨: 지상 4층 | 지상 4층 | 40 | 2690 | 1429.98
7705541 | 지상 4층 | 2650 | 769.983 | 0.0230995 | 0.0612136 | 2.04045 | 2.04045 | 0.0612136 |  | 상위 레벨: 지상 4층 | 지상 4층 | 40 | 2690 | 784.983
7705542 | 지상 4층 | 2650 | 799.983 | 0.0239995 | 0.0635986 | 2.11995 | 2.11995 | 0.0635986 |  | 상위 레벨: 지상 4층 | 지상 4층 | 40 | 2690 | 784.983
7705544 | 지상 5층 | 2650 | 5500 | 0.165 | 0.43725 | 14.575 | 14.575 | 0.43725 | A | 상위 레벨: 지상 5층 | 지상 5층 | 40 | 2690 | 5470
7705545 | 지상 5층 | 2650 | 2690 | 0.0807 | 0.213855 | 7.1285 | 5.0285 | 0.150855 | A | 상위 레벨: 지상 5층 | 지상 5층 | 40 | 2690 | 2720
7705546 | 지상 5층 | 2650 | 3139.98 | 0.0941995 | 0.249629 | 8.32095 | 7.36095 | 0.220829 | A | 상위 레벨: 지상 5층 | 지상 5층 | 40 | 2690 | 3169.98
7705547 | 지상 5층 | 2650 | 3169.98 | 0.0950995 | 0.252014 | 8.40045 | 8.40045 | 0.252014 | A | 상위 레벨: 지상 5층 | 지상 5층 | 40 | 2690 | 3169.98
7705548 | 지상 5층 | 2650 | 1414.98 | 0.0424495 | 0.112491 | 3.7497 | 3.7497 | 0.112491 |  | 상위 레벨: 지상 5층 | 지상 5층 | 40 | 2690 | 1429.98
7705549 | 지상 5층 | 2650 | 1414.98 | 0.0424495 | 0.112491 | 3.7497 | 3.7497 | 0.112491 |  | 상위 레벨: 지상 5층 | 지상 5층 | 40 | 2690 | 1429.98
7705550 | 지상 5층 | 2650 | 769.983 | 0.0230995 | 0.0612136 | 2.04045 | 2.04045 | 0.0612136 |  | 상위 레벨: 지상 5층 | 지상 5층 | 40 | 2690 | 784.983
7705551 | 지상 5층 | 2650 | 799.983 | 0.0239995 | 0.0635986 | 2.11995 | 2.11995 | 0.0635986 |  | 상위 레벨: 지상 5층 | 지상 5층 | 40 | 2690 | 784.983
7705553 | 지상 6층 | 2650 | 5500 | 0.165 | 0.43725 | 14.575 | 14.575 | 0.43725 | A | 상위 레벨: 지상 6층 | 지상 6층 | 40 | 2690 | 5470
7705554 | 지상 6층 | 2650 | 5470 | 0.1641 | 0.434865 | 14.4955 | 12.3955 | 0.371865 | A | 상위 레벨: 지상 6층 | 지상 6층 | 40 | 2690 | 5470
7705555 | 지상 6층 | 2650 | 3139.98 | 0.0941995 | 0.249629 | 8.32095 | 7.36095 | 0.220829 | A | 상위 레벨: 지상 6층 | 지상 6층 | 40 | 2690 | 3169.98
7705556 | 지상 6층 | 2650 | 3169.98 | 0.0950995 | 0.252014 | 8.40045 | 8.40045 | 0.252014 | A | 상위 레벨: 지상 6층 | 지상 6층 | 40 | 2690 | 3169.98
7705557 | 지상 6층 | 2650 | 1414.98 | 0.0424495 | 0.112491 | 3.7497 | 3.7497 | 0.112491 |  | 상위 레벨: 지상 6층 | 지상 6층 | 40 | 2690 | 1429.98
7705558 | 지상 6층 | 2650 | 1414.98 | 0.0424495 | 0.112491 | 3.7497 | 3.7497 | 0.112491 |  | 상위 레벨: 지상 6층 | 지상 6층 | 40 | 2690 | 1429.98
7705559 | 지상 6층 | 2650 | 769.983 | 0.0230995 | 0.0612136 | 2.04045 | 2.04045 | 0.0612136 |  | 상위 레벨: 지상 6층 | 지상 6층 | 40 | 2690 | 784.983
7705560 | 지상 6층 | 2650 | 769.983 | 0.0230995 | 0.0612136 | 2.04045 | 2.04045 | 0.0612136 |  | 상위 레벨: 지상 6층 | 지상 6층 | 40 | 2690 | 784.983
7705562 | 지상 7층 | 2650 | 5500 | 0.165 | 0.43725 | 14.575 | 14.575 | 0.43725 | A | 상위 레벨: 지상 7층 | 지상 7층 | 40 | 2690 | 5470
7705563 | 지상 7층 | 2650 | 2690 | 0.0807 | 0.213855 | 7.1285 | 5.0285 | 0.150855 | A | 상위 레벨: 지상 7층 | 지상 7층 | 40 | 2690 | 2720
7705564 | 지상 7층 | 2650 | 3139.98 | 0.0941995 | 0.249629 | 8.32095 | 7.36095 | 0.220829 | A | 상위 레벨: 지상 7층 | 지상 7층 | 40 | 2690 | 3169.98
7705565 | 지상 7층 | 2650 | 3169.98 | 0.0950995 | 0.252014 | 8.40045 | 8.40045 | 0.252014 | A | 상위 레벨: 지상 7층 | 지상 7층 | 40 | 2690 | 3169.98
7705566 | 지상 7층 | 2650 | 1414.98 | 0.0424495 | 0.112491 | 3.7497 | 3.7497 | 0.112491 |  | 상위 레벨: 지상 7층 | 지상 7층 | 40 | 2690 | 1429.98
7705567 | 지상 7층 | 2650 | 1414.98 | 0.0424495 | 0.112491 | 3.7497 | 3.7497 | 0.112491 |  | 상위 레벨: 지상 7층 | 지상 7층 | 40 | 2690 | 1429.98
7705568 | 지상 7층 | 2650 | 799.983 | 0.0239995 | 0.0635986 | 2.11995 | 2.11995 | 0.0635986 |  | 상위 레벨: 지상 7층 | 지상 7층 | 40 | 2690 | 784.983
7705569 | 지상 7층 | 2650 | 799.983 | 0.0239995 | 0.0635986 | 2.11995 | 2.11995 | 0.0635986 |  | 상위 레벨: 지상 7층 | 지상 7층 | 40 | 2690 | 784.983
7705571 | 지상 8층 | 2650 | 5500 | 0.165 | 0.43725 | 14.575 | 14.575 | 0.43725 | A | 상위 레벨: 지상 8층 | 지상 8층 | 40 | 2690 | 5470
7705572 | 지상 8층 | 2650 | 2690 | 0.0807 | 0.213855 | 7.1285 | 5.0285 | 0.150855 | A | 상위 레벨: 지상 8층 | 지상 8층 | 40 | 2690 | 2720
7705573 | 지상 8층 | 2650 | 3139.98 | 0.0941995 | 0.249629 | 8.32095 | 7.36095 | 0.220829 | A | 상위 레벨: 지상 8층 | 지상 8층 | 40 | 2690 | 3169.98
7705574 | 지상 8층 | 2650 | 3169.98 | 0.0950995 | 0.252014 | 8.40045 | 8.40045 | 0.252014 | A | 상위 레벨: 지상 8층 | 지상 8층 | 40 | 2690 | 3169.98
7705575 | 지상 8층 | 2650 | 1414.98 | 0.0424495 | 0.112491 | 3.7497 | 3.7497 | 0.112491 |  | 상위 레벨: 지상 8층 | 지상 8층 | 40 | 2690 | 1429.98
7705576 | 지상 8층 | 2650 | 1414.98 | 0.0424495 | 0.112491 | 3.7497 | 3.7497 | 0.112491 |  | 상위 레벨: 지상 8층 | 지상 8층 | 40 | 2690 | 1429.98
7705577 | 지상 8층 | 2650 | 769.983 | 0.0230995 | 0.0612136 | 2.04045 | 2.04045 | 0.0612136 |  | 상위 레벨: 지상 8층 | 지상 8층 | 40 | 2690 | 784.983
7705578 | 지상 8층 | 2650 | 799.983 | 0.0239995 | 0.0635986 | 2.11995 | 2.11995 | 0.0635986 |  | 상위 레벨: 지상 8층 | 지상 8층 | 40 | 2690 | 784.983
7705580 | 지상 9층 | 2650 | 5500 | 0.165 | 0.43725 | 14.575 | 14.575 | 0.43725 | A | 상위 레벨: 지상 9층 | 지상 9층 | 40 | 2690 | 5470
7705581 | 지상 9층 | 2650 | 2690 | 0.0807 | 0.213855 | 7.1285 | 5.0285 | 0.150855 | A | 상위 레벨: 지상 9층 | 지상 9층 | 40 | 2690 | 2720
7705582 | 지상 9층 | 2650 | 3139.98 | 0.0941995 | 0.249629 | 8.32095 | 7.36095 | 0.220829 | A | 상위 레벨: 지상 9층 | 지상 9층 | 40 | 2690 | 3169.98
7705583 | 지상 9층 | 2650 | 3169.98 | 0.0950995 | 0.252014 | 8.40045 | 8.40045 | 0.252014 | A | 상위 레벨: 지상 9층 | 지상 9층 | 40 | 2690 | 3169.98
7705584 | 지상 9층 | 2650 | 1414.98 | 0.0424495 | 0.112491 | 3.7497 | 3.7497 | 0.112491 |  | 상위 레벨: 지상 9층 | 지상 9층 | 40 | 2690 | 1429.98
7705585 | 지상 9층 | 2650 | 1414.98 | 0.0424495 | 0.112491 | 3.7497 | 3.7497 | 0.112491 |  | 상위 레벨: 지상 9층 | 지상 9층 | 40 | 2690 | 1429.98
7705586 | 지상 9층 | 2650 | 799.983 | 0.0239995 | 0.0635986 | 2.11995 | 2.11995 | 0.0635986 |  | 상위 레벨: 지상 9층 | 지상 9층 | 40 | 2690 | 784.983
7705587 | 지상 9층 | 2650 | 799.983 | 0.0239995 | 0.0635986 | 2.11995 | 2.11995 | 0.0635986 |  | 상위 레벨: 지상 9층 | 지상 9층 | 40 | 2690 | 784.983
7707327 | 지상 2층 | 2700 | 4399.93 | 0.131998 | 0.356395 | 11.8798 | 11.8798 | 0.356395 | A | 상위 레벨: 지상 2층 | 지상 2층 | 0 | 2700 | 4369.93
7707328 | 지상 2층 | 2700 | 2540 | 0.0762 | 0.20574 | 6.858 | 6.858 | 0.20574 | A | 상위 레벨: 지상 2층 | 지상 2층 | 0 | 2700 | 2570
7707329 | 지상 2층 | 2700 | 4384.93 | 0.131548 | 0.35518 | 11.8393 | 9.73932 | 0.29218 | A | 상위 레벨: 지상 2층 | 지상 2층 | 0 | 2700 | 4369.93
7707511 | 지상 3층 | 2700 | 4399.93 | 0.131998 | 0.356395 | 11.8798 | 11.8798 | 0.356395 | A | 상위 레벨: 지상 3층 | 지상 3층 | 0 | 2700 | 4369.93
7707512 | 지상 3층 | 2700 | 2540 | 0.0762 | 0.20574 | 6.858 | 6.858 | 0.20574 | A | 상위 레벨: 지상 3층 | 지상 3층 | 0 | 2700 | 2570
7707513 | 지상 3층 | 2700 | 4384.93 | 0.131548 | 0.35518 | 11.8393 | 9.73932 | 0.29218 | A | 상위 레벨: 지상 3층 | 지상 3층 | 0 | 2700 | 4369.93
7707515 | 지상 4층 | 2700 | 4399.93 | 0.131998 | 0.356395 | 11.8798 | 11.8798 | 0.356395 | A | 상위 레벨: 지상 4층 | 지상 4층 | 0 | 2700 | 4369.93
7707516 | 지상 4층 | 2700 | 2540 | 0.0762 | 0.20574 | 6.858 | 6.858 | 0.20574 | A | 상위 레벨: 지상 4층 | 지상 4층 | 0 | 2700 | 2570
7707517 | 지상 4층 | 2700 | 4384.93 | 0.131548 | 0.35518 | 11.8393 | 9.73932 | 0.29218 | A | 상위 레벨: 지상 4층 | 지상 4층 | 0 | 2700 | 4369.93
7707519 | 지상 5층 | 2700 | 4399.93 | 0.131998 | 0.356395 | 11.8798 | 11.8798 | 0.356395 | A | 상위 레벨: 지상 5층 | 지상 5층 | 0 | 2700 | 4369.93
7707520 | 지상 5층 | 2700 | 2540 | 0.0762 | 0.20574 | 6.858 | 6.858 | 0.20574 | A | 상위 레벨: 지상 5층 | 지상 5층 | 0 | 2700 | 2570
7707521 | 지상 5층 | 2700 | 4400 | 0.132 | 0.3564 | 11.88 | 9.78 | 0.2934 | A | 상위 레벨: 지상 5층 | 지상 5층 | 0 | 2700 | 4385
7707523 | 지상 6층 | 2700 | 4400 | 0.132 | 0.3564 | 11.88 | 11.88 | 0.3564 | A | 상위 레벨: 지상 6층 | 지상 6층 | 0 | 2700 | 4370
7707524 | 지상 6층 | 2700 | 2540 | 0.0762 | 0.20574 | 6.858 | 6.858 | 0.20574 | A | 상위 레벨: 지상 6층 | 지상 6층 | 0 | 2700 | 2570
7707525 | 지상 6층 | 2700 | 4400 | 0.132 | 0.3564 | 11.88 | 9.78 | 0.2934 | A | 상위 레벨: 지상 6층 | 지상 6층 | 0 | 2700 | 4385
7707527 | 지상 7층 | 2700 | 4399.93 | 0.131998 | 0.356395 | 11.8798 | 11.8798 | 0.356395 | A | 상위 레벨: 지상 7층 | 지상 7층 | 0 | 2700 | 4369.93
7707528 | 지상 7층 | 2700 | 2540 | 0.0762 | 0.20574 | 6.858 | 6.858 | 0.20574 | A | 상위 레벨: 지상 7층 | 지상 7층 | 0 | 2700 | 2570
7707529 | 지상 7층 | 2700 | 4400 | 0.132 | 0.3564 | 11.88 | 9.78 | 0.2934 | A | 상위 레벨: 지상 7층 | 지상 7층 | 0 | 2700 | 4385
7707531 | 지상 8층 | 2700 | 4399.93 | 0.131998 | 0.356395 | 11.8798 | 11.8798 | 0.356395 | A | 상위 레벨: 지상 8층 | 지상 8층 | 0 | 2700 | 4369.93
7707532 | 지상 8층 | 2700 | 2540 | 0.0762 | 0.20574 | 6.858 | 6.858 | 0.20574 | A | 상위 레벨: 지상 8층 | 지상 8층 | 0 | 2700 | 2570
7707533 | 지상 8층 | 2700 | 4384.93 | 0.131548 | 0.35518 | 11.8393 | 9.73932 | 0.29218 | A | 상위 레벨: 지상 8층 | 지상 8층 | 0 | 2700 | 4369.93
7707535 | 지상 9층 | 2700 | 4399.93 | 0.131998 | 0.356395 | 11.8798 | 11.8798 | 0.356395 | A | 상위 레벨: 지상 9층 | 지상 9층 | 0 | 2700 | 4369.93
7707536 | 지상 9층 | 2700 | 2540 | 0.0762 | 0.20574 | 6.858 | 6.858 | 0.20574 | A | 상위 레벨: 지상 9층 | 지상 9층 | 0 | 2700 | 2570
7707537 | 지상 9층 | 2700 | 4384.93 | 0.131548 | 0.35518 | 11.8393 | 9.73932 | 0.29218 | A | 상위 레벨: 지상 9층 | 지상 9층 | 0 | 2700 | 4369.93
7708203 | 지상 2층 | 2700 | 2540 | 0.0762 | 0.20574 | 6.858 | 6.468 | 0.19404 | A | 상위 레벨: 지상 2층 | 지상 2층 | 0 | 2700 | 2570
7708262 | 지상 3층 | 2700 | 2540 | 0.0762 | 0.20574 | 6.858 | 6.468 | 0.19404 | A | 상위 레벨: 지상 3층 | 지상 3층 | 0 | 2700 | 2570
7708264 | 지상 4층 | 2700 | 2540 | 0.0762 | 0.20574 | 6.858 | 6.468 | 0.19404 | A | 상위 레벨: 지상 4층 | 지상 4층 | 0 | 2700 | 2570
7708266 | 지상 5층 | 2700 | 2540 | 0.0762 | 0.20574 | 6.858 | 6.468 | 0.19404 | A | 상위 레벨: 지상 5층 | 지상 5층 | 0 | 2700 | 2570
7708268 | 지상 6층 | 2700 | 2540 | 0.0762 | 0.20574 | 6.858 | 6.468 | 0.19404 | A | 상위 레벨: 지상 6층 | 지상 6층 | 0 | 2700 | 2570
7708270 | 지상 7층 | 2700 | 2540 | 0.0762 | 0.20574 | 6.858 | 6.468 | 0.19404 | A | 상위 레벨: 지상 7층 | 지상 7층 | 0 | 2700 | 2570
7708272 | 지상 8층 | 2700 | 2540 | 0.0762 | 0.20574 | 6.858 | 6.468 | 0.19404 | A | 상위 레벨: 지상 8층 | 지상 8층 | 0 | 2700 | 2570
7708274 | 지상 9층 | 2700 | 2540 | 0.0762 | 0.20574 | 6.858 | 6.468 | 0.19404 | A | 상위 레벨: 지상 9층 | 지상 9층 | 0 | 2700 | 2570
7796153 | 지상 5층 | 2650 | 2660 | 0.0798 | 0.21147 | 7.049 | 7.049 | 0.21147 | A | 상위 레벨: 지상 5층 | 지상 5층 | 40 | 2690 | 2690
7798105 | 지상 1층 | 2200 | 2660 | 0.0798 | 0.17556 | 5.852 | 5.852 | 0.17556 | A | 상위 레벨: 지상 1층 | 지상 1층 | -500 | 1700 | 2630
7798224 | 지상 2층 | 2650 | 2630 | 0.0789 | 0.209085 | 6.9695 | 6.9695 | 0.209085 | A | 상위 레벨: 지상 2층 | 지상 2층 | 40 | 2690 | 2630
7798384 | 지상 3층 | 2650 | 2660 | 0.0798 | 0.21147 | 7.049 | 7.049 | 0.21147 | A | 상위 레벨: 지상 3층 | 지상 3층 | 40 | 2690 | 2630
7798540 | 지상 4층 | 2650 | 2660 | 0.0798 | 0.21147 | 7.049 | 7.049 | 0.21147 | A | 상위 레벨: 지상 4층 | 지상 4층 | 40 | 2690 | 2630
7810888 | 지상 7층 | 2650 | 2630 | 0.0789 | 0.209085 | 6.9695 | 6.9695 | 0.209085 | A | 상위 레벨: 지상 7층 | 지상 7층 | 40 | 2690 | 2630
7820653 | 지상 8층 | 2650 | 2660 | 0.0798 | 0.21147 | 7.049 | 7.049 | 0.21147 | A | 상위 레벨: 지상 8층 | 지상 8층 | 40 | 2690 | 2630
7828375 | 지상 9층 | 2650 | 2630 | 0.0789 | 0.209085 | 6.9695 | 6.9695 | 0.209085 | A | 상위 레벨: 지상 9층 | 지상 9층 | 40 | 2690 | 2630

# IfcWallStandardCase: 기본 벽:A2-22-02A-압출스티로폼, BRACKET(STEEL), ALC블록 (150mm) (78)
Type - PredefinedType: STANDARD; Material: WA240-ALC블록벽 35 mm, WA795-(STEEL)BRACKET 65 mm, WA821-압출스티로폼 벽 (본드붙임, 비중0.03) 50mm 50 mm
Type - ID 데이터 - 단가: 0; 유형 이름: A2-22-02A-압출스티로폼, BRACKET(STEEL), ALC블록 (150mm)
Type - 그래픽 - 거친 축척 채우기 색상: 0
Type - 기타 - 카테고리: 벽; KBIMS-부위코드: E24; 불연성재료: 불연재료; 조달청표준공사코드: AFC100+AJM+AOD112322000; 패밀리 이름: 기본 벽
Type - 시공 - 기능: 외부; 끝단부 마무리: 없음; 인서트 부위 마무리: 마무리하지 않음; 폭: 150 mm
Type - 해석 특성 - 거칠기: 1; 열 저항(R): 1.85185; 열 전달 계수(U): 0.54 kg/K/s3; 열 질량: 2.5725; 흡수율: 9290.3
Type - Pset_WallCommon - IsExternal: yes; ThermalTransmittance: 0.54 kg/K/s3
BaseQuantities - Width: 150 mm
공정 - 생성 공정: 새 구성
구속조건 - 매스와 관련됨: no; 베이스 확장 거리: 0 mm; 벽 베이스가 부착됩니다.: no; 상단 확장 거리: 0 mm; 상단이 부착됩니다.: no; 위치선: 마감면:외부
구조 - 구조: no; 구조적 용도: 비교좌장치
기타 - 패밀리: 기본 벽; 유형: A2-22-02A-압출스티로폼, BRACKET(STEEL), ALC블록 (150mm); 유형 ID: 6831947; 패밀리 및 유형: 기본 벽: A2-22-02A-압출스티로폼, BRACKET(STEEL), ALC블록 (150mm)
단면형상 정의 - 단면형상: 수직
Pset_QuantityTakeOff - Reference: A2-22-02A-압출스티로폼, BRACKET(STEEL), ALC블록 (150mm); sets with these values: 2
Pset_WallCommon - LoadBearing: no; ExtendToStructure: no; Reference: A2-22-02A-압출스티로폼, BRACKET(STEEL), ALC블록 (150mm)
Name (기본 벽:A2-22-02A-압출스티로폼, BRACKET(STEEL), ALC블록 (150mm):...) | In | Height (mm) = 미연결 높이 (mm) | Length (mm) | GrossFootprintArea (m2) | GrossVolume (m3) | GrossSideArea (m2) | NetSideArea (m2) | NetVolume (m3) = 체적 (m3) | 룸 경계 | 상단 간격띄우기 (mm) | 베이스 구속조건 | 상단 구속조건 | 베이스 간격띄우기 (mm) | 길이 (mm) | 면적 (m2)
2831632 | 지상 1층 | 5350 | 6200 | 0.93 | 4.7955 | 31.97 | 31.01 | 4.6515 | yes | 0 | 지상 1층 | 상위 레벨: 지상 2층 | -550 | 6165 | 31.01
2831799 | 지상 1층 | 4800 | 16200 | 2.43 | 11.664 | 77.76 | 69.936 | 10.4904 | yes | 0 | 지상 1층 | 상위 레벨: 지상 2층 | 0 | 16315 | 69.936
2834839 | 지상 2층 | 4500 | 6200 | 0.93 | 3.9045 | 26.03 | 25.07 | 3.7605 | yes | 0 | 지상 2층 | 상위 레벨: 지상 3층 | 0 | 6165 | 25.07
2834840 | 지상 2층 | 4500 | 7600 | 1.14 | 5.13 | 34.2 | 31.8 | 4.77 | yes | 0 | 지상 2층 | 상위 레벨: 지상 3층 | 0 | 7600 | 31.8
2834841 | 지상 2층 | 4500 | 16200 | 2.43 | 10.935 | 72.9 | 65.556 | 9.83341 | yes | 0 | 지상 2층 | 상위 레벨: 지상 3층 | 0 | 16315 | 65.556
2835454 | 지상 3층 | 700 | 22250 | 3.33751 | 2.33625 | 15.575 | 15.575 | 2.33625 | no | 0 | 지상 3층 | 상위 레벨: 지상 4층 | 3400 | 22250 | 15.575 | ID 데이터 - 해설: A
2835461 | 지상 3층 | 4100 | 6200 | 0.93 | 3.633 | 24.22 | 23.26 | 3.489 | yes | 0 | 지상 3층 | 상위 레벨: 지상 4층 | 0 | 6165 | 23.26 | ID 데이터 - 해설: AW; 마크: 4
2835462 | 지상 3층 | 4100 | 7600 | 1.14 | 4.674 | 31.16 | 28.76 | 4.314 | yes | 0 | 지상 3층 | 상위 레벨: 지상 4층 | 0 | 7600 | 28.76
2835466 | 지상 4층 | 3400 | 22250 | 3.33751 | 4.47724 | 29.8483 | 29.8483 | 4.47724 | no | -700 | 지상 4층 | 상위 레벨: 지상 5층 | 0 | 22250 | 29.8483 | ID 데이터 - 해설: A
2835467 | 지상 4층 | 700 | 37550 | 5.6325 | 3.94275 | 26.285 | 26.285 | 3.94275 | yes | 0 | 지상 4층 | 상위 레벨: 지상 5층 | 3400 | 37550 | 26.285
2835468 | 지상 4층 | 700 | 28150 | 4.2225 | 2.95575 | 19.705 | 19.705 | 2.95575 | yes | 0 | 지상 4층 | 상위 레벨: 지상 5층 | 3400 | 28225 | 19.705
2835473 | 지상 4층 | 4100 | 6200 | 0.93 | 3.573 | 23.82 | 22.86 | 3.429 | yes | 0 | 지상 4층 | 상위 레벨: 지상 5층 | 0 | 6165 | 22.86
2835474 | 지상 4층 | 4100 | 7600 | 1.14 | 4.674 | 31.16 | 28.76 | 4.314 | yes | 0 | 지상 4층 | 상위 레벨: 지상 5층 | 0 | 7600 | 28.76
2835475 | 지상 4층 | 4100 | 14100.6 | 2.11509 | 8.67188 | 57.8126 | 54.2126 | 8.13188 | yes | 0 | 지상 4층 | 상위 레벨: 지상 5층 | 0 | 16350.6 | 54.2126
2835485 | 지상 5층 | 4100 | 6200 | 0.93 | 3.573 | 23.82 | 22.86 | 3.429 | yes | 0 | 지상 5층 | 상위 레벨: 지상 6층 | 0 | 6165 | 22.86
2835486 | 지상 5층 | 4100 | 7600 | 1.14 | 4.674 | 31.16 | 28.76 | 4.314 | yes | 0 | 지상 5층 | 상위 레벨: 지상 6층 | 0 | 7600 | 28.76
2835487 | 지상 5층 | 4100 | 14100.6 | 2.11509 | 8.67188 | 57.8126 | 54.2126 | 8.13188 | yes | 0 | 지상 5층 | 상위 레벨: 지상 6층 | 0 | 16350.6 | 54.2126
2835497 | 지상 6층 | 4100 | 6200 | 0.93 | 3.573 | 23.82 | 22.86 | 3.429 | yes | 0 | 지상 6층 | 상위 레벨: 지상 7층 | 0 | 6165 | 22.86
2835498 | 지상 6층 | 4100 | 7600 | 1.14 | 4.674 | 31.16 | 28.76 | 4.314 | yes | 0 | 지상 6층 | 상위 레벨: 지상 7층 | 0 | 7600 | 28.76
2835499 | 지상 6층 | 4100 | 14100.6 | 2.11509 | 8.67188 | 57.8126 | 54.2126 | 8.13188 | yes | 0 | 지상 6층 | 상위 레벨: 지상 7층 | 0 | 16500.6 | 54.2126
2835509 | 지상 7층 | 4100 | 6200 | 0.93 | 3.573 | 23.82 | 22.86 | 3.429 | yes | 0 | 지상 7층 | 상위 레벨: 지상 8층 | 0 | 6165 | 22.86
2835510 | 지상 7층 | 4100 | 7600 | 1.14 | 4.674 | 31.16 | 28.76 | 4.314 | yes | 0 | 지상 7층 | 상위 레벨: 지상 8층 | 0 | 7600 | 28.76
2835511 | 지상 7층 | 4100 | 14100.6 | 2.11509 | 8.67188 | 57.8126 | 54.2126 | 8.13188 | yes | 0 | 지상 7층 | 상위 레벨: 지상 8층 | 0 | 16500.6 | 54.2126
2835521 | 지상 8층 | 4100 | 6200 | 0.93 | 3.573 | 23.82 | 22.86 | 3.429 | yes | 0 | 지상 8층 | 상위 레벨: 지상 9층 | 0 | 6165 | 22.86
2835522 | 지상 8층 | 4100 | 7600 | 1.14 | 4.674 | 31.16 | 28.76 | 4.314 | yes | 0 | 지상 8층 | 상위 레벨: 지상 9층 | 0 | 7600 | 28.76
2835523 | 지상 8층 | 4100 | 14100.6 | 2.11509 | 8.67188 | 57.8126 | 54.2126 | 8.13188 | yes | 0 | 지상 8층 | 상위 레벨: 지상 9층 | 0 | 16500.6 | 54.2126
2835526 | 지상 9층 | 1400 | 34800 | 5.22 | 7.308 | 48.72 | 48.72 | 7.308 | no | 0 | 지상 9층 | 상위 레벨: 지상 10층 | 3100 | 34725 | 48.72 | ID 데이터 - 해설: A
2835527 | 지상 9층 | 1400 | 37550 | 5.6325 | 7.8855 | 52.57 | 52.57 | 7.8855 | yes | 0 | 지상 9층 | 상위 레벨: 지상 10층 | 3100 | 37550 | 52.57
2835528 | 지상 9층 | 1400 | 28150 | 4.2225 | 5.9115 | 39.41 | 39.41 | 5.9115 | yes | 0 | 지상 9층 | 상위 레벨: 지상 10층 | 3100 | 28225 | 39.41
2835533 | 지상 9층 | 4500 | 6200 | 0.93 | 3.94287 | 26.2858 | 25.3258 | 3.79887 | yes | 0 | 지상 9층 | 상위 레벨: 지상 10층 | 0 | 6165 | 25.3258
2835534 | 지상 9층 | 4500 | 7600 | 1.14 | 5.13 | 34.2 | 31.8 | 4.77 | yes | 0 | 지상 9층 | 상위 레벨: 지상 10층 | 0 | 7600 | 31.8
2835535 | 지상 9층 | 4500 | 14100.6 | 2.11509 | 9.51792 | 63.4528 | 59.8528 | 8.97792 | yes | 0 | 지상 9층 | 상위 레벨: 지상 10층 | 0 | 16500.6 | 59.8528
2890152 | 옥탑층 | 4700 | 3161.85 | 0.474277 | 2.15113 | 14.3409 | 14.3409 | 2.15113 | yes | 700 | 옥탑층 | 상위 레벨: 지붕층 | 0 | 3081.85 | 14.3409
2990619 | 옥탑층 | 1300 | 28299.5 | 4.24493 | 5.5184 | 36.7894 | 36.7894 | 5.5184 | yes | -2700 | 옥탑층 | 상위 레벨: 지붕층 | 0 | 28224.5 | 36.7894
2990786 | 옥탑층 | 1300 | 37550.6 | 5.63259 | 7.32237 | 48.8158 | 48.8158 | 7.32237 | yes | -2700 | 옥탑층 | 상위 레벨: 지붕층 | 0 | 37550.6 | 48.8158
2991001 | 옥탑층 | 1300 | 14250.6 | 2.13759 | 2.77887 | 18.5258 | 18.5258 | 2.77887 | yes | -2700 | 옥탑층 | 상위 레벨: 지붕층 | 0 | 16350.6 | 18.5258
2991094 | 옥탑층 | 1300 | 7450 | 1.1175 | 1.45275 | 9.685 | 9.685 | 1.45275 | yes | -2700 | 옥탑층 | 상위 레벨: 지붕층 | 0 | 7600 | 9.685
2991161 | 옥탑층 | 1300 | 5020 | 0.753 | 0.9789 | 6.526 | 6.526 | 0.9789 | yes | -2700 | 옥탑층 | 상위 레벨: 지붕층 | 0 | 5020 | 6.526
2997281 | 지상 5층 | 2000 | 168 | 0.0252 | 0.0504 | 0.336 | 0.336 | 0.0504 | yes | -1500 | 지상 5층 | 상위 레벨: 지상 6층 | 600 | 350 | 0.336
2998521 | 지상 3층 | 4100 | 14100.6 | 2.11509 | 8.67188 | 57.8126 | 54.2126 | 8.13188 | yes | 0 | 지상 3층 | 상위 레벨: 지상 4층 | 0 | 16500.6 | 54.2126
5231895 | 옥탑층 | 1300 | 34650.5 | 5.19758 | 6.75685 | 45.0457 | 45.0457 | 6.75685 | no | -2700 | 옥탑층 | 상위 레벨: 지붕층 | 0 | 34725.5 | 45.0457 | ID 데이터 - 해설: A
5892425 | 지상 4층 | 700 | 34800 | 5.22 | 3.654 | 24.36 | 24.36 | 3.654 | no | 0 | 지상 4층 | 상위 레벨: 지상 5층 | 3400 | 34725 | 24.36 | ID 데이터 - 해설: A
5897511 | 지상 3층 | 700 | 15750 | 2.3625 | 1.65375 | 11.025 | 11.025 | 1.65375 | yes | 0 | 지상 3층 | 상위 레벨: 지상 4층 | 3400 | 15750 | 11.025
5897661 | 지상 4층 | 3400 | 15750 | 2.3625 | 8.0325 | 53.55 | 21.2478 | 3.18717 | yes | -700 | 지상 4층 | 상위 레벨: 지상 5층 | 0 | 15750 | 21.2478
5899037 | 지상 9층 | 600 | 34800 | 5.22 | 3.132 | 20.88 | 20.88 | 3.132 | no | 600 | 지상 9층 | 상위 레벨: 지상 9층 | 0 | 34725 | 20.88 | ID 데이터 - 해설: A
5899038 | 지상 9층 | 600 | 37550.6 | 5.63259 | 3.37956 | 22.5304 | 22.5304 | 3.37956 | yes | 600 | 지상 9층 | 상위 레벨: 지상 9층 | 0 | 37550.6 | 22.5304
5899039 | 지상 9층 | 600 | 28150 | 4.2225 | 2.5335 | 16.89 | 16.89 | 2.5335 | yes | 600 | 지상 9층 | 상위 레벨: 지상 9층 | 0 | 28225 | 16.89
5899351 | 지상 7층 | 1500 | 34800 | 5.22 | 7.83 | 52.2 | 52.2 | 7.83 | no | 0 | 지상 7층 | 상위 레벨: 지상 8층 | 2600 | 34725 | 52.2 | ID 데이터 - 해설: A
5899352 | 지상 7층 | 1500 | 37550 | 5.6325 | 8.44875 | 56.325 | 56.325 | 8.44875 | yes | 0 | 지상 7층 | 상위 레벨: 지상 8층 | 2600 | 37550 | 56.325
5899353 | 지상 7층 | 1500 | 28150 | 4.2225 | 6.33375 | 42.225 | 42.225 | 6.33375 | yes | 0 | 지상 7층 | 상위 레벨: 지상 8층 | 2600 | 28225 | 42.225
5899354 | 지상 7층 | 600 | 34800 | 5.22 | 3.132 | 20.88 | 20.88 | 3.132 | no | 600 | 지상 7층 | 상위 레벨: 지상 7층 | 0 | 34725 | 20.88 | ID 데이터 - 해설: A
5899355 | 지상 7층 | 600 | 37550.6 | 5.63259 | 3.37956 | 22.5304 | 22.5304 | 3.37956 | yes | 600 | 지상 7층 | 상위 레벨: 지상 7층 | 0 | 37550.6 | 22.5304
5899356 | 지상 7층 | 600 | 28150 | 4.2225 | 2.5335 | 16.89 | 16.89 | 2.5335 | yes | 600 | 지상 7층 | 상위 레벨: 지상 7층 | 0 | 28225 | 16.89
5899359 | 지상 8층 | 1500 | 34800 | 5.22 | 7.83 | 52.2 | 52.2 | 7.83 | no | 0 | 지상 8층 | 상위 레벨: 지상 9층 | 2600 | 34725 | 52.2 | ID 데이터 - 해설: A
5899360 | 지상 8층 | 1500 | 37550 | 5.6325 | 8.44875 | 56.325 | 56.325 | 8.44875 | yes | 0 | 지상 8층 | 상위 레벨: 지상 9층 | 2600 | 37550 | 56.325
5899361 | 지상 8층 | 1500 | 28150 | 4.2225 | 6.33375 | 42.225 | 42.225 | 6.33375 | yes | 0 | 지상 8층 | 상위 레벨: 지상 9층 | 2600 | 28225 | 42.225
5899362 | 지상 8층 | 600 | 34800 | 5.22 | 3.132 | 20.88 | 20.88 | 3.132 | no | 600 | 지상 8층 | 상위 레벨: 지상 8층 | 0 | 34725 | 20.88 | ID 데이터 - 해설: A
5899363 | 지상 8층 | 600 | 37550 | 5.6325 | 3.3795 | 22.53 | 22.53 | 3.3795 | yes | 600 | 지상 8층 | 상위 레벨: 지상 8층 | 0 | 37550 | 22.53
5899364 | 지상 8층 | 600 | 28150 | 4.2225 | 2.5335 | 16.89 | 16.89 | 2.5335 | yes | 600 | 지상 8층 | 상위 레벨: 지상 8층 | 0 | 28225 | 16.89
5899554 | 지상 5층 | 1500 | 34800 | 5.22 | 7.83 | 52.2 | 52.2 | 7.83 | no | 0 | 지상 5층 | 상위 레벨: 지상 6층 | 2600 | 34725 | 52.2 | ID 데이터 - 해설: A
5899555 | 지상 5층 | 1500 | 37550.6 | 5.63259 | 8.44889 | 56.3259 | 56.3259 | 8.44889 | yes | 0 | 지상 5층 | 상위 레벨: 지상 6층 | 2600 | 37550.6 | 56.3259
5899556 | 지상 5층 | 1500 | 28150 | 4.2225 | 6.33375 | 42.225 | 42.225 | 6.33375 | yes | 0 | 지상 5층 | 상위 레벨: 지상 6층 | 2600 | 28225 | 42.225
5899557 | 지상 5층 | 600 | 34800 | 5.22 | 3.132 | 20.88 | 20.88 | 3.132 | no | 600 | 지상 5층 | 상위 레벨: 지상 5층 | 0 | 34725 | 20.88 | ID 데이터 - 해설: A
5899558 | 지상 5층 | 600 | 37550.6 | 5.63259 | 3.37956 | 22.5304 | 22.5304 | 3.37956 | yes | 600 | 지상 5층 | 상위 레벨: 지상 5층 | 0 | 37550.6 | 22.5304
5899559 | 지상 5층 | 600 | 28150 | 4.2225 | 2.5335 | 16.89 | 16.89 | 2.5335 | yes | 600 | 지상 5층 | 상위 레벨: 지상 5층 | 0 | 28225 | 16.89
5899562 | 지상 6층 | 1500 | 34800 | 5.22 | 7.83 | 52.2 | 52.2 | 7.83 | no | 0 | 지상 6층 | 상위 레벨: 지상 7층 | 2600 | 34725 | 52.2 | ID 데이터 - 해설: A
5899563 | 지상 6층 | 1500 | 37550 | 5.6325 | 8.44875 | 56.325 | 56.325 | 8.44875 | yes | 0 | 지상 6층 | 상위 레벨: 지상 7층 | 2600 | 37550 | 56.325
5899564 | 지상 6층 | 1500 | 28150 | 4.2225 | 6.33375 | 42.225 | 42.225 | 6.33375 | yes | 0 | 지상 6층 | 상위 레벨: 지상 7층 | 2600 | 28225 | 42.225
5899565 | 지상 6층 | 600 | 34800 | 5.22 | 3.132 | 20.88 | 20.88 | 3.132 | no | 600 | 지상 6층 | 상위 레벨: 지상 6층 | 0 | 34725 | 20.88 | ID 데이터 - 해설: A
5899566 | 지상 6층 | 600 | 37550.6 | 5.63259 | 3.37956 | 22.5304 | 22.5304 | 3.37956 | yes | 600 | 지상 6층 | 상위 레벨: 지상 6층 | 0 | 37550.6 | 22.5304
5899567 | 지상 6층 | 600 | 28150 | 4.2225 | 2.5335 | 16.89 | 16.89 | 2.5335 | yes | 600 | 지상 6층 | 상위 레벨: 지상 6층 | 0 | 28225 | 16.89
5900249 | 지상 6층 | 2000 | 168 | 0.0252 | 0.0504 | 0.336 | 0.336 | 0.0504 | yes | -1500 | 지상 6층 | 상위 레벨: 지상 7층 | 600 | 350 | 0.336
5900252 | 지상 7층 | 2000 | 350 | 0.0525 | 0.105 | 0.7 | 0.7 | 0.105 | yes | -1500 | 지상 7층 | 상위 레벨: 지상 8층 | 600 | 350 | 0.7
5900255 | 지상 8층 | 2000 | 168 | 0.0252 | 0.0504 | 0.336 | 0.336 | 0.0504 | yes | -1500 | 지상 8층 | 상위 레벨: 지상 9층 | 600 | 350 | 0.336
5900258 | 지상 9층 | 2500 | 350 | 0.0525 | 0.13125 | 0.875 | 0.875 | 0.13125 | yes | -1400 | 지상 9층 | 상위 레벨: 지상 10층 | 600 | 350 | 0.875
5900261 | 지상 10층 | 3000 | 150 | 0.0225 | 0.0675 | 0.45 | 0.45 | 0.0674999 | yes | -1400 | 지상 10층 | 상위 레벨: 옥탑층 | 600 | 350 | 0.449999
7722410 | 지상 10층 | 5000 | 749.974 | 0.112496 | 0.56248 | 3.74987 | 3.74987 | 0.56248 | yes | 0 | 지상 10층 | 상위 레벨: 옥탑층 | 0 | 674.974 | 3.74987
7722411 | 지상 10층 | 5000 | 600 | 0.09 | 0.45 | 3 | 3 | 0.45 | yes | 0 | 지상 10층 | 상위 레벨: 옥탑층 | 0 | 675 | 3

# IfcWallStandardCase: 기본 벽:A2-26-01A-압출스티로폼, 금속 긴결철물, 금속외장패널 (150mm) (44)
Type - PredefinedType: STANDARD; Material: WA785-금속외장패널 25 mm, WA793-금속 긴결철물 벽 75 mm, WA821-압출스티로폼 벽 (본드붙임, 비중0.03) 50mm 50 mm
Type - ID 데이터 - 단가: 0; 유형 이름: A2-26-01A-압출스티로폼, 금속 긴결철물, 금속외장패널 (150mm)
Type - 그래픽 - 거친 축척 채우기 색상: 0
Type - 기타 - 카테고리: 벽; KBIMS-부위코드: E24; 불연성재료: 불연재료; 조달청표준공사코드: AJN+AJM4+AOD112322000; 패밀리 이름: 기본 벽
Type - 시공 - 기능: 외부; 끝단부 마무리: 없음; 인서트 부위 마무리: 마무리하지 않음; 폭: 150 mm
Type - 해석 특성 - 거칠기: 1; 열 저항(R): 1.85185; 열 전달 계수(U): 0.54 kg/K/s3; 열 질량: 2.5725; 흡수율: 9290.3
Type - Pset_WallCommon - IsExternal: yes; ThermalTransmittance: 0.54 kg/K/s3
BaseQuantities - Width: 150 mm
공정 - 생성 공정: 새 구성
구속조건 - 매스와 관련됨: no; 베이스 확장 거리: 0 mm; 벽 베이스가 부착됩니다.: no; 상단 확장 거리: 0 mm; 상단이 부착됩니다.: no; 위치선: 마감면:외부
구조 - 구조: no; 구조적 용도: 비교좌장치
기타 - 패밀리: 기본 벽; 유형: A2-26-01A-압출스티로폼, 금속 긴결철물, 금속외장패널 (150mm); 유형 ID: 6832219; 패밀리 및 유형: 기본 벽: A2-26-01A-압출스티로폼, 금속 긴결철물, 금속외장패널 (150mm)
단면형상 정의 - 단면형상: 수직
Pset_QuantityTakeOff - Reference: A2-26-01A-압출스티로폼, 금속 긴결철물, 금속외장패널 (150mm); sets with these values: 2
Pset_WallCommon - LoadBearing: no; ExtendToStructure: no; Reference: A2-26-01A-압출스티로폼, 금속 긴결철물, 금속외장패널 (150mm)
Name (기본 벽:A2-26-01A-압출스티로폼, 금속 긴결철물, 금속외장패널 (150mm):...) | In | Height (mm) | Length (mm) | GrossFootprintArea (m2) | GrossVolume (m3) | GrossSideArea (m2) | NetSideArea (m2) = 면적 (m2) | NetVolume (m3) = 체적 (m3) | 베이스 간격띄우기 (mm) | 룸 경계 | 상단 간격띄우기 (mm) | 베이스 구속조건 | 상단 구속조건 | 미연결 높이 (mm) | 길이 (mm)
2835481 | 지상 5층 | 4100 | 10925 | 1.63875 | 6.71888 | 44.7925 | 41.1925 | 6.17888 | 0 | yes | 0 | 지상 5층 | 상위 레벨: 지상 6층 | 4100 | 10850
2835493 | 지상 6층 | 4100 | 10775 | 1.61625 | 6.62663 | 44.1775 | 40.5775 | 6.08663 | 0 | yes | 0 | 지상 6층 | 상위 레벨: 지상 7층 | 4100 | 10850
2835505 | 지상 7층 | 4100 | 10775 | 1.61625 | 6.62662 | 44.1775 | 40.5775 | 6.08662 | 0 | yes | 0 | 지상 7층 | 상위 레벨: 지상 8층 | 4100 | 10850
2835517 | 지상 8층 | 4100 | 10775 | 1.61625 | 6.62662 | 44.1775 | 40.5775 | 6.08662 | 0 | yes | 0 | 지상 8층 | 상위 레벨: 지상 9층 | 4100 | 10850
2835529 | 지상 9층 | 4500 | 10775 | 1.61625 | 7.27313 | 48.4875 | 44.8875 | 6.73313 | 0 | yes | 0 | 지상 9층 | 상위 레벨: 지상 10층 | 4500 | 10850
2835541 | 지상 10층 | 5000 | 850 | 0.1275 | 0.6375 | 4.25 | 4.25 | 0.6375 | 0 | yes | 0 | 지상 10층 | 상위 레벨: 옥탑층 | 5000 | 775
2995675 | 지상 4층 | 5500 | 10925 | 1.63875 | 9.01313 | 60.0875 | 56.4875 | 8.47313 | -1400 | yes | 0 | 지상 4층 | 상위 레벨: 지상 5층 | 5500 | 10850
2996001 | 옥탑층 | 4698 | 10925.5 | 1.63883 | 7.6992 | 51.328 | 51.328 | 7.6992 | 0 | yes | 698 | 옥탑층 | 상위 레벨: 지붕층 | 4698 | 10850.5
2997054 | 지상 4층 | 5500 | 550 | 0.0825 | 0.45375 | 3.025 | 3.025 | 0.45375 | -1400 | yes | 0 | 지상 4층 | 상위 레벨: 지상 5층 | 5500 | 625
2997533 | 지상 6층 | 4100 | 700 | 0.105 | 0.4305 | 2.87 | 2.87 | 0.4305 | 0 | yes | 0 | 지상 6층 | 상위 레벨: 지상 7층 | 4100 | 625
2997536 | 지상 7층 | 4100 | 700 | 0.105 | 0.4305 | 2.87 | 2.87 | 0.4305 | 0 | yes | 0 | 지상 7층 | 상위 레벨: 지상 8층 | 4100 | 625
2997539 | 지상 8층 | 4100 | 700 | 0.105 | 0.4305 | 2.87 | 2.87 | 0.4305 | 0 | yes | 0 | 지상 8층 | 상위 레벨: 지상 9층 | 4100 | 625
2997542 | 지상 9층 | 4500 | 700 | 0.105 | 0.4725 | 3.15 | 3.15 | 0.4725 | 0 | yes | 0 | 지상 9층 | 상위 레벨: 지상 10층 | 4500 | 625
2997545 | 지상 10층 | 5000 | 550 | 0.0825 | 0.4125 | 2.75 | 2.75 | 0.4125 | 0 | yes | 0 | 지상 10층 | 상위 레벨: 옥탑층 | 5000 | 625
2997548 | 옥탑층 | 4698 | 551 | 0.08265 | 0.38829 | 2.5886 | 2.5886 | 0.38829 | 0 | yes | 698 | 옥탑층 | 상위 레벨: 지붕층 | 4698 | 626
3153345 | 지상 4층 | 4100 | 2099.38 | 0.314908 | 1.29112 | 8.60748 | 8.60748 | 1.29112 | 0 | yes | 0 | 지상 4층 | 상위 레벨: 지상 5층 | 4100 | 2174.38
3538874 | 지상 4층 | 4100 | 700 | 0.105 | 0.4305 | 2.87 | 2.87 | 0.4305 | 0 | yes | 0 | 지상 4층 | 상위 레벨: 지상 5층 | 4100 | 625
5231647 | 지상 3층 | 1400 | 2099.38 | 0.314908 | 0.440871 | 2.93914 | 2.93914 | 0.440871 | 2650 | yes | 0 | 지상 3층 | 상위 레벨: 지상 4층 | 1450 | 2174.38
5231648 | 지상 3층 | 1450 | 700 | 0.00746087 | 0.147373 | 0.982487 | 0.982487 | 0.147373 | 2650 | yes | 0 | 지상 3층 | 상위 레벨: 지상 4층 | 1450 | 625
5231719 | 지상 5층 | 4100 | 2100 | 0.315 | 1.2915 | 8.61 | 8.61 | 1.2915 | 0 | yes | 0 | 지상 5층 | 상위 레벨: 지상 6층 | 4100 | 2175
5231720 | 지상 5층 | 4100 | 700 | 0.105 | 0.4305 | 2.87 | 2.87 | 0.4305 | 0 | yes | 0 | 지상 5층 | 상위 레벨: 지상 6층 | 4100 | 625
5231723 | 지상 6층 | 4100 | 2099.38 | 0.314908 | 1.29112 | 8.60748 | 8.60748 | 1.29112 | 0 | yes | 0 | 지상 6층 | 상위 레벨: 지상 7층 | 4100 | 2174.38
5231724 | 지상 6층 | 4100 | 700 | 0.105 | 0.4305 | 2.87 | 2.87 | 0.4305 | 0 | yes | 0 | 지상 6층 | 상위 레벨: 지상 7층 | 4100 | 625
5231727 | 지상 7층 | 4100 | 2099.38 | 0.314908 | 1.29112 | 8.60748 | 8.60748 | 1.29112 | 0 | yes | 0 | 지상 7층 | 상위 레벨: 지상 8층 | 4100 | 2174.38
5231728 | 지상 7층 | 4100 | 700 | 0.105 | 0.4305 | 2.87 | 2.87 | 0.4305 | 0 | yes | 0 | 지상 7층 | 상위 레벨: 지상 8층 | 4100 | 625
5231731 | 지상 8층 | 4100 | 2099.38 | 0.314908 | 1.29112 | 8.60748 | 8.60748 | 1.29112 | 0 | yes | 0 | 지상 8층 | 상위 레벨: 지상 9층 | 4100 | 2174.38
5231732 | 지상 8층 | 4100 | 700 | 0.105 | 0.4305 | 2.87 | 2.87 | 0.4305 | 0 | yes | 0 | 지상 8층 | 상위 레벨: 지상 9층 | 4100 | 625
5231735 | 지상 9층 | 4500 | 2099.38 | 0.314908 | 1.41708 | 9.44723 | 9.44723 | 1.41708 | 0 | yes | 0 | 지상 9층 | 상위 레벨: 지상 10층 | 4500 | 2174.38
5231736 | 지상 9층 | 4500 | 700 | 0.105 | 0.4725 | 3.15 | 3.15 | 0.4725 | 0 | yes | 0 | 지상 9층 | 상위 레벨: 지상 10층 | 4500 | 625
5231740 | 지상 10층 | 5000 | 700 | 0.105 | 0.525 | 3.5 | 3.5 | 0.525 | 0 | yes | 0 | 지상 10층 | 상위 레벨: 옥탑층 | 5000 | 625
5536581 | 옥탑층 | 4698 | 2247.98 | 0.337197 | 1.58415 | 10.561 | 10.561 | 1.58415 | 0 | no | 698 | 옥탑층 | 상위 레벨: 지붕층 | 4698 | 2172.98 | ID 데이터 - 해설: A
5536583 | 옥탑층 | 4000 | 549.5 | 0.082425 | 0.3297 | 2.198 | 2.198 | 0.3297 | 0 | no | 0 | 옥탑층 | 상위 레벨: 지붕층 | 4000 | 624.5 | ID 데이터 - 해설: A
5892869 | 지상 3층 | 700 | 22950 | 3.4425 | 2.40975 | 16.065 | 16.065 | 2.40975 | 2700 | no | -700 | 지상 3층 | 상위 레벨: 지상 4층 | 700 | 22950 | ID 데이터 - 해설: A
5893932 | 지상 3층 | 700 | 699.965 | 0.104995 | 0.0734963 | 0.489976 | 0.489976 | 0.0734963 | 3400 | no | 0 | 지상 3층 | 상위 레벨: 지상 4층 | 700 | 699.965 | ID 데이터 - 해설: A
5894083 | 지상 4층 | 700 | 11850 | 1.7775 | 1.24425 | 8.295 | 8.295 | 1.24425 | 2700 | no | 3400 | 지상 4층 | 상위 레벨: 지상 4층 | 700 | 11775 | ID 데이터 - 해설: A
5895322 | 지상 4층 | 3400 | 699.965 | 0.104995 | 0.356982 | 2.37988 | 2.37988 | 0.356982 | 0 | no | 3400 | 지상 4층 | 상위 레벨: 지상 4층 | 3400 | 699.965 | ID 데이터 - 해설: A
5896228 | 지상 4층 | 700 | 37550 | 5.6325 | 3.94275 | 26.285 | 26.285 | 3.94275 | 2700 | yes | 3400 | 지상 4층 | 상위 레벨: 지상 4층 | 700 | 37550
5896412 | 지상 4층 | 700 | 12400 | 1.86 | 1.302 | 8.68 | 8.68 | 1.302 | 2700 | yes | 3400 | 지상 4층 | 상위 레벨: 지상 4층 | 700 | 12475
5896797 | 지상 4층 | 2700 | 700.035 | 0.105005 | 0.283514 | 1.89009 | 1.89009 | 0.283514 | 0 | yes | 2700 | 지상 4층 | 상위 레벨: 지상 4층 | 2700 | 700.035
5896958 | 지상 3층 | 1400 | 700.035 | 0.105005 | 0.147007 | 0.980049 | 0.980049 | 0.147007 | 2700 | yes | 0 | 지상 3층 | 상위 레벨: 지상 4층 | 1400 | 700.035
5897395 | 지상 3층 | 700 | 15745 | 2.36174 | 1.65322 | 11.0215 | 11.0215 | 1.65322 | 2700 | yes | -700 | 지상 3층 | 상위 레벨: 지상 4층 | 700 | 15745
5900100 | 지상 5층 | 4100 | 550 | 0.0825 | 0.33825 | 2.255 | 2.255 | 0.33825 | 0 | yes | 0 | 지상 5층 | 상위 레벨: 지상 6층 | 4100 | 625
7718526 | 지상 10층 | 5000 | 775 | 0.11625 | 0.58125 | 3.875 | 3.875 | 0.58125 | 0 | yes | 0 | 지상 10층 | 상위 레벨: 옥탑층 | 5000 | 775
7722010 | 지상 10층 | 5000 | 700 | 0.105 | 0.525 | 3.5 | 3.5 | 0.525 | 0 | yes | 0 | 지상 10층 | 상위 레벨: 옥탑층 | 5000 | 775

# IfcWallStandardCase: 기본 벽:WA111-철근콘크리트구조 벽 125mm_W3 (20)
Type - PredefinedType: STANDARD; Material: KBIMS-콘크리트 125 mm
Type - ID 데이터 - 단가: 0; 유형 마크: W3; 유형 이름: WA111-철근콘크리트구조 벽 125mm_W3
Type - 그래픽 - 거친 축척 채우기 색상: 0
Type - 기타 - 내화구조여부: yes; 주요구조부여부: yes; 카테고리: 벽; KBIMS-부위코드: E275; 조달청표준공사코드: AD; 패밀리 이름: 기본 벽
Type - 시공 - 기능: 외부; 끝단부 마무리: 없음; 인서트 부위 마무리: 마무리하지 않음; 폭: 125 mm
Type - 재료 및 마감재 - 구조 재료: KBIMS-콘크리트
Type - 해석 특성 - 거칠기: 1; 열 저항(R): 0.119503; 열 전달 계수(U): 8.368 kg/K/s3; 열 질량: 188.887; 흡수율: 9290.3
Type - Pset_WallCommon - IsExternal: yes; ThermalTransmittance: 8.368 kg/K/s3
BaseQuantities - Width: 125 mm
공정 - 생성 공정: 새 구성
구속조건 - 매스와 관련됨: no; 룸 경계: yes; 베이스 확장 거리: 0 mm; 벽 베이스가 부착됩니다.: no; 상단 간격띄우기: 0 mm; 상단 확장 거리: 0 mm; 상단이 부착됩니다.: no
기타 - 패밀리: 기본 벽; 유형: WA111-철근콘크리트구조 벽 125mm_W3; 유형 ID: 7431068; 패밀리 및 유형: 기본 벽: WA111-철근콘크리트구조 벽 125mm_W3
단면형상 정의 - 단면형상: 수직
Pset_QuantityTakeOff - Reference: WA111-철근콘크리트구조 벽 125mm_W3; sets with these values: 2
Pset_WallCommon - ExtendToStructure: no; Reference: WA111-철근콘크리트구조 벽 125mm_W3
Name (기본 벽:WA111-철근콘크리트구조 벽 125mm_W3:...) | In | Height (mm) | Length (mm) | GrossFootprintArea (m2) | GrossVolume (m3) | GrossSideArea (m2) | NetSideArea (m2) = 면적 (m2) | NetVolume (m3) = 체적 (m3) | 연관 있음 | 베이스 간격띄우기 (mm) | 위치선 | 베이스 구속조건 | 상단 구속조건 | 미연결 높이 (mm) | 구조 = LoadBearing | 보강 철근 피복 - 다른 면 = 보강 철근 피복 - 내부 면 = 보강 철근 피복 - 외부 면 | 구조적 용도 | 길이 (mm)
5381982 | 지상 2층 | 4350 | 7250 | 0.90625 | 1.13419 | 9.0735 | 9.0735 | 1.13419 | yes | 0 | 구조체 면:외부 | 지상 2층 | 상위 레벨: 지상 3층 | 4500 | yes | 보강 철근 피복 1 <25 mm> | 교좌장치 | 7241
5382011 | 지상 2층 | 4350 | 6600.02 | 0.825002 | 1.01475 | 8.11802 | 8.11802 | 1.01475 | yes | 0 | 구조체 면:외부 | 지상 2층 | 상위 레벨: 지상 3층 | 4500 | yes | 보강 철근 피복 1 <25 mm> | 교좌장치 | 6582.02
5382021 | 지상 2층 | 4350 | 6500 | 0.8125 | 0.999375 | 7.995 | 7.995 | 0.999375 | yes | 0 | 구조체 면:외부 | 지상 2층 | 상위 레벨: 지상 3층 | 4500 | yes | 보강 철근 피복 1 <25 mm> | 교좌장치 | 6491
5382032 | 지상 2층 | 4350 | 10882 | 1.36025 | 2.14218 | 17.1374 | 17.1374 | 2.14218 | yes | 0 | 구조체 면:외부 | 지상 2층 | 상위 레벨: 지상 3층 | 4500 | yes | 보강 철근 피복 1 <25 mm> | 교좌장치 | 10891
5382043 | 지상 2층 | 4350 | 11882 | 1.48525 | 2.2168 | 17.7344 | 17.7344 | 2.2168 | yes | 0 | 구조체 면:외부 | 지상 2층 | 상위 레벨: 지상 3층 | 4500 | yes | 보강 철근 피복 1 <25 mm> | 교좌장치 | 11891
5382057 | 지상 2층 | 4350 | 2499.98 | 0.312498 | 0.384372 | 3.07498 | 3.07498 | 0.384372 | yes | 0 | 구조체 면:외부 | 지상 2층 | 상위 레벨: 지상 3층 | 4500 | yes | 보강 철근 피복 1 <25 mm> | 교좌장치 | 2499.98
5382073 | 지상 2층 | 4350 | 9932 | 1.2415 | 3.66219 | 29.2975 | 15.4141 | 1.92676 | yes | 0 | 구조체 면:외부 | 지상 2층 | 상위 레벨: 지상 3층 | 4500 | yes | 보강 철근 피복 1 <25 mm> | 교좌장치 | 9941
5382087 | 지상 2층 | 4350 | 9064.01 | 1.133 | 1.7831 | 14.2648 | 14.2648 | 1.7831 | yes | 0 | 구조체 면:외부 | 지상 2층 | 상위 레벨: 지상 3층 | 4500 | yes | 보강 철근 피복 1 <25 mm> | 교좌장치 | 9082.01
5382097 | 지상 2층 | 4350 | 10864 | 1.358 | 2.07984 | 16.6387 | 16.6387 | 2.07984 | yes | 0 | 구조체 면:외부 | 지상 2층 | 상위 레벨: 지상 3층 | 4500 | yes | 보강 철근 피복 1 <25 mm> | 교좌장치 | 10882
5382111 | 지상 2층 | 4350 | 6482 | 0.81025 | 0.996607 | 7.97286 | 7.97286 | 0.996607 | yes | 0 | 구조체 면:외부 | 지상 2층 | 상위 레벨: 지상 3층 | 4500 | yes | 보강 철근 피복 1 <25 mm> | 교좌장치 | 6482
5382125 | 지상 2층 | 4350 | 8101 | 1.01263 | 1.24592 | 9.96735 | 9.96735 | 1.24592 | yes | 0 | 구조체 면:외부 | 지상 2층 | 상위 레벨: 지상 3층 | 4500 | yes | 보강 철근 피복 1 <25 mm> | 교좌장치 | 8083
5431504 | 지상 1층 | 4800 | 7200.02 | 0.900002 | 1.152 | 9.21602 | 9.21602 | 1.152 |  | 0 | 마감면:내부 | 지상 1층 | 상위 레벨: 지상 2층 | 4800 | no |  | 비교좌장치 | 7182.02
5431681 | 지상 1층 | 4800 | 6600 | 0.825 | 1.056 | 8.448 | 8.448 | 1.056 |  | 0 | 구조체 면:외부 | 지상 1층 | 상위 레벨: 지상 2층 | 4800 | no |  | 비교좌장치 | 6582
5432100 | 지상 1층 | 4800 | 10900 | 1.3625 | 1.744 | 13.952 | 13.952 | 1.744 |  | 0 | 구조체 면:외부 | 지상 1층 | 상위 레벨: 지상 2층 | 4800 | no |  | 비교좌장치 | 10882
5432236 | 지상 1층 | 4800 | 11900 | 1.4875 | 1.904 | 15.232 | 15.232 | 1.904 |  | 0 | 구조체 면:외부 | 지상 1층 | 상위 레벨: 지상 2층 | 4800 | no |  | 비교좌장치 | 11882
5432344 | 지상 1층 | 4650 | 9900 | 1.2375 | 1.39838 | 11.187 | 11.187 | 1.39838 |  | 0 | 구조체 면:외부 | 지상 1층 | 상위 레벨: 지상 2층 | 4800 | no |  | 비교좌장치 | 9891
5432458 | 지상 1층 | 4800 | 9100 | 1.1375 | 1.46392 | 11.7114 | 11.7114 | 1.46392 |  | 0 | 구조체 면:외부 | 지상 1층 | 상위 레벨: 지상 2층 | 4800 | no |  | 비교좌장치 | 9091
5432560 | 지상 1층 | 4800 | 10900 | 1.3625 | 1.744 | 13.952 | 13.952 | 1.744 |  | 0 | 구조체 면:외부 | 지상 1층 | 상위 레벨: 지상 2층 | 4800 | no |  | 비교좌장치 | 10891
5432926 | 지상 1층 | 6300 | 8062.5 | 1.00781 | 6.34922 | 50.7938 | 10.7241 | 1.34051 |  | -1500 | 구조체 면:외부 | 지상 1층 | 상위 레벨: 지상 2층 | 6300 | no |  | 비교좌장치 | 8053.5
5433044 | 지상 1층 | 5300 | 6537.5 | 0.817187 | 1.046 | 8.368 | 8.368 | 1.046 |  | -500 | 구조체 면:외부 | 지상 1층 | 상위 레벨: 지상 2층 | 5300 | no |  | 비교좌장치 | 6537.5

# IfcWallStandardCase: 기본 벽:WA111-철근콘크리트구조 벽 200mm_BT1, 기본 벽:WA111-철근콘크리트구조 벽 200mm_BT1:2817791
In: 지하1층
Type - PredefinedType: STANDARD; Material: KBIMS-콘크리트 200 mm
Type - ID 데이터 - 단가: 0; 유형 마크: BT1; 유형 이름: WA111-철근콘크리트구조 벽 200mm_BT1
Type - 그래픽 - 거친 축척 채우기 색상: 0
Type - 기타 - 내화구조여부: yes; 주요구조부여부: yes; 카테고리: 벽; KBIMS-부위코드: E275; 조달청표준공사코드: AD; 패밀리 이름: 기본 벽
Type - 시공 - 기능: 외부; 끝단부 마무리: 없음; 인서트 부위 마무리: 마무리하지 않음; 폭: 200 mm
Type - 재료 및 마감재 - 구조 재료: KBIMS-콘크리트
Type - 해석 특성 - 거칠기: 1; 열 저항(R): 0.191205; 열 전달 계수(U): 5.23 kg/K/s3; 열 질량: 302.22; 흡수율: 9290.3
Type - Pset_WallCommon - IsExternal: yes; ThermalTransmittance: 5.23 kg/K/s3
BaseQuantities - Height: 5950 mm; Length: 3210.97 mm; Width: 200 mm; GrossFootprintArea: 0.614197 m2; GrossVolume: 3.82105 m3; GrossSideArea: 19.1053 m2; NetSideArea: 19.1053 m2; NetVolume: 3.65447 m3
ID 데이터 - 연관 있음: yes
공정 - 생성 공정: 새 구성
구속조건 - 베이스 간격띄우기: 0 mm; 매스와 관련됨: no; 룸 경계: yes; 베이스 확장 거리: 0 mm; 벽 베이스가 부착됩니다.: no; 상단 간격띄우기: 0 mm; 상단 확장 거리: 0 mm; 상단이 부착됩니다.: no; 위치선: 구조체 면:외부; 베이스 구속조건: 지하1층; 상단 구속조건: 상위 레벨: 지상 1층; 미연결 높이: 6100 mm
구조 - 구조: yes; 보강 철근 피복 - 다른 면: 보강 철근 피복 1 <25 mm>; 구조적 용도: 교좌장치; 보강 철근 피복 - 내부 면: 보강 철근 피복 1 <25 mm>; 보강 철근 피복 - 외부 면: 보강 철근 피복 1 <25 mm>
기타 - 패밀리: 기본 벽; 유형: WA111-철근콘크리트구조 벽 200mm_BT1; 유형 ID: 7629825; 패밀리 및 유형: 기본 벽: WA111-철근콘크리트구조 벽 200mm_BT1
단면형상 정의 - 단면형상: 수직
치수 - 길이: 3695.65 mm; 면적: 19.1053 m2; 체적: 3.65447 m3
Pset_QuantityTakeOff - Reference: WA111-철근콘크리트구조 벽 200mm_BT1; sets with these values: 2
Pset_WallCommon - LoadBearing: yes; ExtendToStructure: no; Reference: WA111-철근콘크리트구조 벽 200mm_BT1

# IfcWallStandardCase: 기본 벽:WA111-철근콘크리트구조 벽 200mm_CW1 (252)
Type - PredefinedType: STANDARD; Material: KBIMS-콘크리트 200 mm
Type - ID 데이터 - 단가: 0; 유형 마크: CW1; 유형 이름: WA111-철근콘크리트구조 벽 200mm_CW1
Type - 그래픽 - 거친 축척 채우기 색상: 0
Type - 기타 - 내화구조여부: yes; 주요구조부여부: yes; 카테고리: 벽; KBIMS-부위코드: E275; 조달청표준공사코드: AD; 패밀리 이름: 기본 벽
Type - 시공 - 기능: 외부; 끝단부 마무리: 없음; 인서트 부위 마무리: 마무리하지 않음; 폭: 200 mm
Type - 재료 및 마감재 - 구조 재료: KBIMS-콘크리트
Type - 해석 특성 - 거칠기: 1; 열 저항(R): 0.191205; 열 전달 계수(U): 5.23 kg/K/s3; 열 질량: 302.22; 흡수율: 9290.3
Type - Pset_WallCommon - ThermalTransmittance: 5.23 kg/K/s3; IsExternal: yes
BaseQuantities - Width: 200 mm
공정 - 생성 공정: 새 구성
구속조건 - 매스와 관련됨: no; 룸 경계: yes; 베이스 확장 거리: 0 mm; 벽 베이스가 부착됩니다.: no; 상단 확장 거리: 0 mm
기타 - 유형: WA111-철근콘크리트구조 벽 200mm_CW1; 유형 ID: 7430341; 패밀리: 기본 벽; 패밀리 및 유형: 기본 벽: WA111-철근콘크리트구조 벽 200mm_CW1
단면형상 정의 - 단면형상: 수직
Pset_QuantityTakeOff - Reference: WA111-철근콘크리트구조 벽 200mm_CW1; sets with these values: 2
Pset_WallCommon - Reference: WA111-철근콘크리트구조 벽 200mm_CW1
Name (기본 벽:WA111-철근콘크리트구조 벽 200mm_CW1:...) | In | Height (mm) | Length (mm) | GrossFootprintArea (m2) | GrossVolume (m3) | GrossSideArea (m2) | NetSideArea (m2) | NetVolume (m3) = 체적 (m3) | 연관 있음 | 베이스 간격띄우기 (mm) | 상단 간격띄우기 (mm) | 베이스 구속조건 | 상단 구속조건 | 상단이 부착됩니다. = ExtendToStructure | 위치선 | 미연결 높이 (mm) | 구조 = LoadBearing | 보강 철근 피복 - 다른 면 | 구조적 용도 | 보강 철근 피복 - 내부 면 = 보강 철근 피복 - 외부 면 | 길이 (mm) | 면적 (m2)
2813273 | 지하2층 | 4000 | 5501.85 | 1.10037 | 4.40148 | 22.0074 | 22.0074 | 4.40148 | yes | 0 | 0 | 지하2층 | 상위 레벨: 지하1층 | no | 구조체 면:외부 | 4000 | yes | 보강 철근 피복 1 <25 mm> | 교좌장치 | 보강 철근 피복 1 <25 mm> | 5701.85 | 22.0074
2813404 | 지하2층 | 4000 | 5500 | 1.1 | 4.4 | 22 | 22 | 4.4 | yes | 0 | 0 | 지하2층 | 상위 레벨: 지하1층 | no | 구조체 면:외부 | 4000 | yes | 보강 철근 피복 1 <25 mm> | 교좌장치 | 보강 철근 피복 1 <25 mm> | 5700 | 22
2813669 | 지하2층 | 4000 | 3200 | 0.64 | 2.56 | 12.8 | 12.8 | 2.56 | yes | 0 | 0 | 지하2층 | 상위 레벨: 지하1층 | no | 구조체 면:외부 | 4000 | yes | 보강 철근 피복 1 <25 mm> | 교좌장치 | 보강 철근 피복 1 <25 mm> | 3200 | 12.8
2813740 | 지하2층 | 4000 | 2800 | 0.56 | 2.24 | 11.2 | 11.2 | 2.24 | yes | 0 | 0 | 지하2층 | 상위 레벨: 지하1층 | no | 구조체 면:외부 | 4000 | yes | 보강 철근 피복 1 <25 mm> | 교좌장치 | 보강 철근 피복 1 <25 mm> | 3000 | 11.2
2813846 | 지하2층 | 4000 | 2501.85 | 0.500369 | 2.00148 | 10.0074 | 10.0074 | 2.00148 | yes | 0 | 0 | 지하2층 | 상위 레벨: 지하1층 | no | 구조체 면:외부 | 4000 | yes | 보강 철근 피복 1 <25 mm> | 교좌장치 | 보강 철근 피복 1 <25 mm> | 2701.85 | 10.0074
2813950 | 지하2층 | 4000 | 5501.85 | 1.10037 | 0.16 | 0.8 | 21.0474 | 4.20948 | yes | 0 | 0 | 지하2층 | 상위 레벨: 지하1층 | no | 구조체 면:외부 | 4000 | yes | 보강 철근 피복 1 <25 mm> | 교좌장치 | 보강 철근 피복 1 <25 mm> | 5701.85 | 21.0474
2814153 | 지하2층 | 3850 | 4797.24 | 0.95957 | 3.69388 | 18.4694 | 14.6894 | 2.93834 | yes | 0 | 0 | 지하2층 | 상위 레벨: 지하1층 | no | 구조체 면:외부 | 4000 | yes | 보강 철근 피복 1 <25 mm> | 교좌장치 | 보강 철근 피복 1 <25 mm> | 5198.15 | 14.6894
2816461 | 지하1층 | 5500 | 5501.85 | 1.10037 | 6.00249 | 30.0124 | 30.0124 | 6.00249 | yes | 0 | -600 | 지하1층 | 상위 레벨: 지상 1층 | no | 구조체 면:외부 | 5500 | yes | 보강 철근 피복 1 <25 mm> | 교좌장치 | 보강 철근 피복 1 <25 mm> | 5701.85 | 30.0124
2816463 | 지하1층 | 6100 | 13081 | 2.61411 | 0.756 | 3.78 | 76.0139 | 15.1901 | yes | 0 | 0 | 지하1층 | 상위 레벨: 지상 1층 | no | 구조체 면:외부 | 6100 | yes | 보강 철근 피복 1 <25 mm> | 교좌장치 | 보강 철근 피복 1 <25 mm> | 13272.6 | 76.0139
2816467 | 지하1층 | 5500 | 6300 | 1.26 | 0.378 | 1.89 | 31.66 | 6.332 | yes | 0 | -600 | 지하1층 | 상위 레벨: 지상 1층 | no | 구조체 면:외부 | 5500 | yes | 보강 철근 피복 1 <25 mm> | 교좌장치 | 보강 철근 피복 1 <25 mm> | 6900 | 31.66
2816469 | 지하1층 | 6100 | 5500 | 1.1 | 6.71 | 33.55 | 33.55 | 6.71 | yes | 0 | 0 | 지하1층 | 상위 레벨: 지상 1층 | no | 구조체 면:외부 | 6100 | yes | 보강 철근 피복 1 <25 mm> | 교좌장치 | 보강 철근 피복 1 <25 mm> | 5700 | 33.55
2818041 | 지상 1층 | 4650 | 5901.85 | 1.18037 | 0.561 | 2.805 | 21.8336 | 4.36672 | yes | 0 | 0 | 지상 1층 | 상위 레벨: 지상 2층 | no | 구조체 면:외부 | 4800 | yes | 보강 철근 피복 1 <25 mm> | 교좌장치 | 보강 철근 피복 1 <25 mm> | 5701.85 | 21.8336
2818045 | 지상 1층 | 4800 | 5500 | 1.1 | 5.28 | 26.4 | 26.4 | 5.28 | yes | 0 | 0 | 지상 1층 | 상위 레벨: 지상 2층 | no | 구조체 면:외부 | 4800 | yes | 보강 철근 피복 1 <25 mm> | 교좌장치 | 보강 철근 피복 1 <25 mm> | 5700 | 26.4
2818049 | 지상 1층 | 4800 | 3203.91 | 0.640782 | 3.07575 | 15.3788 | 15.3788 | 3.07575 | yes | 0 | 0 | 지상 1층 | 상위 레벨: 지상 2층 | no | 구조체 면:외부 | 4800 | yes | 보강 철근 피복 1 <25 mm> | 교좌장치 | 보강 철근 피복 1 <25 mm> | 3203.91 | 15.3788
2818051 | 지상 1층 | 4800 | 2800 | 0.56 | 2.688 | 13.44 | 13.44 | 2.688 | yes | 0 | 0 | 지상 1층 | 상위 레벨: 지상 2층 | no | 구조체 면:외부 | 4800 | yes | 보강 철근 피복 1 <25 mm> | 교좌장치 | 보강 철근 피복 1 <25 mm> | 3000 | 13.44
2818053 | 지상 1층 | 4800 | 2501.85 | 0.500369 | 2.40177 | 12.0089 | 12.0089 | 2.40177 | yes | 0 | 0 | 지상 1층 | 상위 레벨: 지상 2층 | no | 구조체 면:외부 | 4800 | yes | 보강 철근 피복 1 <25 mm> | 교좌장치 | 보강 철근 피복 1 <25 mm> | 2701.85 | 12.0089
2818055 | 지상 1층 | 4800 | 5501.85 | 1.10037 | 5.28177 | 26.4089 | 25.4489 | 5.08977 | yes | 0 | 0 | 지상 1층 | 상위 레벨: 지상 2층 | no | 구조체 면:외부 | 4800 | yes | 보강 철근 피복 1 <25 mm> | 교좌장치 | 보강 철근 피복 1 <25 mm> | 5701.85 | 25.4489
2818061 | 지상 1층 | 3550 | 3898.57 | 0.779714 | 2.76798 | 13.8399 | 12.8799 | 2.57598 | yes | -550 | 3000 | 지상 1층 | 상위 레벨: 지상 1층 | no | 구조체 면:외부 | 3550 | yes | 보강 철근 피복 1 <25 mm> | 교좌장치 | 보강 철근 피복 1 <25 mm> | 3873.57 | 12.8799
2818536 | 지상 1층 | 4650 | 6503.91 | 1.30078 | 5.84064 | 29.2032 | 29.2032 | 5.84064 | yes | 0 | 0 | 지상 1층 | 상위 레벨: 지상 2층 | no | 구조체 면:외부 | 4800 | yes | 보강 철근 피복 1 <25 mm> | 교좌장치 | 보강 철근 피복 1 <25 mm> | 6703.91 | 29.2032
2818908 | 지상 1층 | 4800 | 2800 | 0.56 | 2.688 | 13.44 | 13.44 | 2.688 | yes | -200 | 0 | 지상 1층 | 상위 레벨: 지상 2층 | no | 구조체 면:외부 | 5000 | yes | 보강 철근 피복 1 <25 mm> | 교좌장치 | 보강 철근 피복 1 <25 mm> | 2800 | 13.44
2818910 | 지상 1층 | 5200 | 6700 | 1.34 | 0.462 | 2.31 | 31 | 6.2 | yes | -550 | 0 | 지상 1층 | 상위 레벨: 지상 2층 | no | 구조체 면:외부 | 5350 | yes | 보강 철근 피복 1 <25 mm> | 교좌장치 | 보강 철근 피복 1 <25 mm> | 6700 | 31
2818912 | 지상 1층 | 5400 | 2800 | 0.56 | 3.024 | 15.12 | 14.73 | 2.946 | yes | -600 | 0 | 지상 1층 | 상위 레벨: 지상 2층 | no | 구조체 면:외부 | 5400 | yes | 보강 철근 피복 1 <25 mm> | 교좌장치 | 보강 철근 피복 1 <25 mm> | 2800 | 14.73
2819016 | 지상 1층 | 4800 | 2600 | 0.52 | 2.496 | 12.48 | 12.48 | 2.496 | yes | 0 | 0 | 지상 1층 | 상위 레벨: 지상 2층 | no | 구조체 면:외부 | 4800 | yes | 보강 철근 피복 1 <25 mm> | 교좌장치 | 보강 철근 피복 1 <25 mm> | 2800 | 12.48
2819152 | 지상 1층 | 5200 | 4600 | 0.92 | 4.348 | 21.74 | 21.74 | 4.348 | yes | -550 | 0 | 지상 1층 | 상위 레벨: 지상 2층 | no | 구조체 면:외부 | 5350 | yes | 보강 철근 피복 1 <25 mm> | 교좌장치 | 보강 철근 피복 1 <25 mm> | 4600 | 21.74
2820022 | 지상 2층 | 4500 | 6200 | 1.24 | 5.206 | 26.03 | 25.07 | 5.014 | yes | 0 | 0 | 지상 2층 | 상위 레벨: 지상 3층 | no | 구조체 면:외부 | 4500 | yes | 보강 철근 피복 1 <25 mm> | 교좌장치 | 보강 철근 피복 1 <25 mm> | 6200 | 25.07
2820024 | 지상 2층 | 4350 | 12503.9 | 2.50078 | 10.8784 | 54.392 | 49.152 | 9.8304 | yes | 0 | 0 | 지상 2층 | 상위 레벨: 지상 3층 | no | 구조체 면:외부 | 4500 | yes | 보강 철근 피복 1 <25 mm> | 교좌장치 | 보강 철근 피복 1 <25 mm> | 12403.9 | 49.152
2820026 | 지상 2층 | 4350 | 5700.01 | 1.14 | 4.95901 | 24.795 | 19.185 | 3.83701 | yes | 0 | 0 | 지상 2층 | 상위 레벨: 지상 3층 | no | 구조체 면:외부 | 4500 | yes | 보강 철근 피복 1 <25 mm> | 교좌장치 | 보강 철근 피복 1 <25 mm> | 5700.01 | 19.185
2820028 | 지상 2층 | 4500 | 5700 | 1.14 | 5.014 | 25.07 | 22.97 | 4.539 | yes | 0 | 0 | 지상 2층 | 상위 레벨: 지상 3층 | no | 구조체 면:외부 | 4500 | yes | 보강 철근 피복 1 <25 mm> | 교좌장치 | 보강 철근 피복 1 <25 mm> | 5700 | 22.695
2820030 | 지상 2층 | 4500 | 5500 | 1.1 | 4.95 | 24.75 | 24.75 | 4.95 | yes | 0 | 0 | 지상 2층 | 상위 레벨: 지상 3층 | no | 구조체 면:외부 | 4500 | yes | 보강 철근 피복 1 <25 mm> | 교좌장치 | 보강 철근 피복 1 <25 mm> | 5700 | 24.75
2820034 | 지상 2층 | 4500 | 3203.91 | 0.640782 | 2.88352 | 14.4176 | 14.4176 | 2.88352 | yes | 0 | 0 | 지상 2층 | 상위 레벨: 지상 3층 | no | 구조체 면:외부 | 4500 | yes | 보강 철근 피복 1 <25 mm> | 교좌장치 | 보강 철근 피복 1 <25 mm> | 3203.91 | 14.4176
2820036 | 지상 2층 | 4500 | 2800 | 0.56 | 2.52 | 12.6 | 12.6 | 2.52 | yes | 0 | 0 | 지상 2층 | 상위 레벨: 지상 3층 | no | 구조체 면:외부 | 4500 | yes | 보강 철근 피복 1 <25 mm> | 교좌장치 | 보강 철근 피복 1 <25 mm> | 3000 | 12.6
2820038 | 지상 2층 | 4500 | 2500.01 | 0.500002 | 2.25001 | 11.25 | 11.25 | 2.25001 | yes | 0 | 0 | 지상 2층 | 상위 레벨: 지상 3층 | no | 구조체 면:외부 | 4500 | yes | 보강 철근 피복 1 <25 mm> | 교좌장치 | 보강 철근 피복 1 <25 mm> | 2700.01 | 11.25
2820040 | 지상 2층 | 4500 | 5500.01 | 1.1 | 4.84501 | 24.225 | 23.265 | 4.65301 | yes | 0 | 0 | 지상 2층 | 상위 레벨: 지상 3층 | no | 구조체 면:외부 | 4500 | yes | 보강 철근 피복 1 <25 mm> | 교좌장치 | 보강 철근 피복 1 <25 mm> | 5700.01 | 23.265
2820048 | 지상 2층 | 4350 | 6503.91 | 1.30078 | 5.6584 | 28.292 | 27.252 | 5.4504 | yes | 0 | 0 | 지상 2층 | 상위 레벨: 지상 3층 | no | 구조체 면:외부 | 4500 | yes | 보강 철근 피복 1 <25 mm> | 교좌장치 | 보강 철근 피복 1 <25 mm> | 6703.91 | 27.252
2820050 | 지상 2층 | 4350 | 2800 | 0.56 | 2.436 | 12.18 | 8.4 | 1.68 | yes | 0 | 0 | 지상 2층 | 상위 레벨: 지상 3층 | no | 구조체 면:외부 | 4500 | yes | 보강 철근 피복 1 <25 mm> | 교좌장치 | 보강 철근 피복 1 <25 mm> | 2800 | 8.4
2820052 | 지상 2층 | 4350 | 6700 | 1.34 | 5.829 | 29.145 | 28.755 | 5.751 | yes | 0 | 0 | 지상 2층 | 상위 레벨: 지상 3층 | no | 구조체 면:외부 | 4500 | yes | 보강 철근 피복 1 <25 mm> | 교좌장치 | 보강 철근 피복 1 <25 mm> | 6700 | 28.755
2820054 | 지상 2층 | 4500 | 2800 | 0.56 | 2.514 | 12.57 | 12.18 | 2.436 | yes | 0 | 0 | 지상 2층 | 상위 레벨: 지상 3층 | no | 구조체 면:외부 | 4500 | yes | 보강 철근 피복 1 <25 mm> | 교좌장치 | 보강 철근 피복 1 <25 mm> | 2800 | 12.18
2820056 | 지상 2층 | 4350 | 6700 | 1.34 | 5.829 | 29.145 | 29.145 | 5.829 | yes | 0 | 0 | 지상 2층 | 상위 레벨: 지상 3층 | no | 구조체 면:외부 | 4500 | yes | 보강 철근 피복 1 <25 mm> | 교좌장치 | 보강 철근 피복 1 <25 mm> | 6700 | 29.145
2820058 | 지상 2층 | 4500 | 2600 | 0.52 | 2.34 | 11.7 | 11.7 | 2.34 | yes | 0 | 0 | 지상 2층 | 상위 레벨: 지상 3층 | no | 구조체 면:외부 | 4500 | yes | 보강 철근 피복 1 <25 mm> | 교좌장치 | 보강 철근 피복 1 <25 mm> | 2800 | 11.7
2820060 | 지상 2층 | 4350 | 4400 | 0.88 | 3.828 | 19.14 | 17.04 | 3.408 | yes | 0 | 0 | 지상 2층 | 상위 레벨: 지상 3층 | no | 구조체 면:외부 | 4500 | yes | 보강 철근 피복 1 <25 mm> | 교좌장치 | 보강 철근 피복 1 <25 mm> | 4600 | 17.04
2820062 | 지상 2층 | 4500 | 4300 | 0.86 | 3.819 | 19.095 | 16.469 | 3.2938 | yes | 0 | 0 | 지상 2층 | 상위 레벨: 지상 3층 | no | 구조체 면:외부 | 4500 | yes | 보강 철근 피복 1 <25 mm> | 교좌장치 | 보강 철근 피복 1 <25 mm> | 4500 | 16.469
2820064 | 지상 2층 | 4350 | 5999.98 | 1.2 | 5.21998 | 26.0999 | 26.0999 | 5.21998 | yes | 0 | 0 | 지상 2층 | 상위 레벨: 지상 3층 | no | 구조체 면:외부 | 4500 | yes | 보강 철근 피복 1 <25 mm> | 교좌장치 | 보강 철근 피복 1 <25 mm> | 6099.98 | 26.0999
2820066 | 지상 2층 | 4350 | 9100.01 | 1.82 | 2.31946 | 11.5973 | 11.5973 | 2.31946 | yes | 0 | 0 | 지상 2층 | 상위 레벨: 지상 3층 | no | 구조체 면:외부 | 4500 | yes | 보강 철근 피복 1 <25 mm> | 교좌장치 | 보강 철근 피복 1 <25 mm> | 9100.01 | 11.5973
2820441 | 지상 3층 | 4100 | 6200 | 1.24 | 4.87 | 24.35 | 23.39 | 4.678 | yes | 0 | 0 | 지상 3층 | 상위 레벨: 지상 4층 | no | 구조체 면:외부 | 4100 | yes | 보강 철근 피복 1 <25 mm> | 교좌장치 | 보강 철근 피복 1 <25 mm> | 6200 | 23.39
2820447 | 지상 3층 | 4100 | 5700 | 1.05001 | 4.503 | 22.515 | 20.618 | 4.0758 | yes | 0 | 0 | 지상 3층 | 상위 레벨: 지상 4층 | no | 구조체 면:외부 | 4100 | yes | 보강 철근 피복 1 <25 mm> | 교좌장치 | 보강 철근 피복 1 <25 mm> | 5700 | 20.415
2820449 | 지상 3층 | 4100 | 5500 | 1.1 | 4.51 | 22.55 | 22.55 | 4.51 | yes | 0 | 0 | 지상 3층 | 상위 레벨: 지상 4층 | no | 구조체 면:외부 | 4100 | yes | 보강 철근 피복 1 <25 mm> | 교좌장치 | 보강 철근 피복 1 <25 mm> | 5700 | 22.55
2820453 | 지상 3층 | 4100 | 3199.91 | 0.639982 | 2.62393 | 13.1196 | 13.1196 | 2.62393 | yes | 0 | 0 | 지상 3층 | 상위 레벨: 지상 4층 | no | 구조체 면:외부 | 4100 | yes | 보강 철근 피복 1 <25 mm> | 교좌장치 | 보강 철근 피복 1 <25 mm> | 3199.91 | 13.1196
2820455 | 지상 3층 | 4100 | 2800 | 0.56 | 2.296 | 11.48 | 11.48 | 2.296 | yes | 0 | 0 | 지상 3층 | 상위 레벨: 지상 4층 | no | 구조체 면:외부 | 4100 | yes | 보강 철근 피복 1 <25 mm> | 교좌장치 | 보강 철근 피복 1 <25 mm> | 3000 | 11.48
2820457 | 지상 3층 | 4100 | 2500.01 | 0.500002 | 2.05001 | 10.25 | 10.25 | 2.05001 | yes | 0 | 0 | 지상 3층 | 상위 레벨: 지상 4층 | no | 구조체 면:외부 | 4100 | yes | 보강 철근 피복 1 <25 mm> | 교좌장치 | 보강 철근 피복 1 <25 mm> | 2700.01 | 10.25
2820459 | 지상 3층 | 4100 | 5500.01 | 1.1 | 4.40501 | 22.025 | 21.065 | 4.21301 | yes | 0 | 0 | 지상 3층 | 상위 레벨: 지상 4층 | no | 구조체 면:외부 | 4100 | yes | 보강 철근 피복 1 <25 mm> | 교좌장치 | 보강 철근 피복 1 <25 mm> | 5700.01 | 21.065
2820469 | 지상 3층 | 3950 | 6695 | 1.339 | 5.28905 | 26.4453 | 26.0553 | 5.21105 | yes | 0 | 0 | 지상 3층 | 상위 레벨: 지상 4층 | no | 구조체 면:외부 | 4100 | yes | 보강 철근 피복 1 <25 mm> | 교좌장치 | 보강 철근 피복 1 <25 mm> | 6695 | 26.0553
2820471 | 지상 3층 | 4100 | 2800 | 0.56 | 2.29 | 11.45 | 11.06 | 2.212 | yes | 0 | 0 | 지상 3층 | 상위 레벨: 지상 4층 | no | 구조체 면:외부 | 4100 | yes | 보강 철근 피복 1 <25 mm> | 교좌장치 | 보강 철근 피복 1 <25 mm> | 2800 | 11.06
2820473 | 지상 3층 | 3950 | 6695 | 1.339 | 5.28905 | 26.4453 | 26.4453 | 5.28905 | yes | 0 | 0 | 지상 3층 | 상위 레벨: 지상 4층 | no | 구조체 면:외부 | 4100 | yes | 보강 철근 피복 1 <25 mm> | 교좌장치 | 보강 철근 피복 1 <25 mm> | 6695 | 26.4453
2820475 | 지상 3층 | 4100 | 2600 | 0.52 | 2.132 | 10.66 | 10.66 | 2.132 | yes | 0 | 0 | 지상 3층 | 상위 레벨: 지상 4층 | no | 구조체 면:외부 | 4100 | yes | 보강 철근 피복 1 <25 mm> | 교좌장치 | 보강 철근 피복 1 <25 mm> | 2800 | 10.66
2820477 | 지상 3층 | 3950 | 4400 | 0.88 | 3.0416 | 15.208 | 15.208 | 3.0416 | yes | 0 | 0 | 지상 3층 | 상위 레벨: 지상 4층 | no | 구조체 면:외부 | 4100 | yes | 보강 철근 피복 1 <25 mm> | 교좌장치 | 보강 철근 피복 1 <25 mm> | 4600 | 15.208
2820479 | 지상 3층 | 4100 | 4300 | 0.86 | 3.475 | 17.375 | 14.85 | 2.97 | yes | 0 | 0 | 지상 3층 | 상위 레벨: 지상 4층 | no | 구조체 면:외부 | 4100 | yes | 보강 철근 피복 1 <25 mm> | 교좌장치 | 보강 철근 피복 1 <25 mm> | 4500 | 14.85
2820481 | 지상 3층 | 3950 | 6000 | 1.2 | 4.74 | 23.7 | 23.7 | 4.74 | yes | 0 | 0 | 지상 3층 | 상위 레벨: 지상 4층 | no | 구조체 면:외부 | 4100 | yes | 보강 철근 피복 1 <25 mm> | 교좌장치 | 보강 철근 피복 1 <25 mm> | 6100 | 23.7
2820691 | 지상 4층 | 4100 | 6200 | 1.24 | 4.764 | 23.82 | 22.86 | 4.572 | yes | 0 | 0 | 지상 4층 | 상위 레벨: 지상 5층 | no | 구조체 면:외부 | 4100 | yes | 보강 철근 피복 1 <25 mm> | 교좌장치 | 보강 철근 피복 1 <25 mm> | 6200 | 22.86
2820693 | 지상 4층 | 3950 | 12499.9 | 2.49998 | 9.87493 | 49.3746 | 44.1346 | 8.82693 | yes | 0 | 0 | 지상 4층 | 상위 레벨: 지상 5층 | no | 구조체 면:외부 | 4100 | yes | 보강 철근 피복 1 <25 mm> | 교좌장치 | 보강 철근 피복 1 <25 mm> | 12399.9 | 44.1346
2820695 | 지상 4층 | 3950 | 5700.01 | 1.14 | 4.50301 | 22.515 | 16.905 | 3.38101 | yes | 0 | 0 | 지상 4층 | 상위 레벨: 지상 5층 | no | 구조체 면:외부 | 4100 | yes | 보강 철근 피복 1 <25 mm> | 교좌장치 | 보강 철근 피복 1 <25 mm> | 5700.01 | 16.905
2820699 | 지상 4층 | 4100 | 5500 | 1.1 | 4.51 | 22.55 | 22.55 | 4.51 | yes | 0 | 0 | 지상 4층 | 상위 레벨: 지상 5층 | no | 구조체 면:외부 | 4100 | yes | 보강 철근 피복 1 <25 mm> | 교좌장치 | 보강 철근 피복 1 <25 mm> | 5700 | 22.55
2820703 | 지상 4층 | 4100 | 3199.91 | 0.639982 | 2.62393 | 13.1196 | 13.1196 | 2.62393 | yes | 0 | 0 | 지상 4층 | 상위 레벨: 지상 5층 | no | 구조체 면:외부 | 4100 | yes | 보강 철근 피복 1 <25 mm> | 교좌장치 | 보강 철근 피복 1 <25 mm> | 3199.91 | 13.1196
2820705 | 지상 4층 | 4100 | 2799.92 | 0.559985 | 2.29594 | 11.4797 | 11.4797 | 2.29594 | yes | 0 | 0 | 지상 4층 | 상위 레벨: 지상 5층 | no | 구조체 면:외부 | 4100 | yes | 보강 철근 피복 1 <25 mm> | 교좌장치 | 보강 철근 피복 1 <25 mm> | 2999.92 | 11.4797
2820707 | 지상 4층 | 4100 | 2500.09 | 0.500017 | 2.05007 | 10.2504 | 10.2504 | 2.05007 | yes | 0 | 0 | 지상 4층 | 상위 레벨: 지상 5층 | no | 구조체 면:외부 | 4100 | yes | 보강 철근 피복 1 <25 mm> | 교좌장치 | 보강 철근 피복 1 <25 mm> | 2700.09 | 10.2504
2820709 | 지상 4층 | 4100 | 5500.01 | 1.1 | 4.51001 | 22.55 | 21.59 | 4.31801 | yes | 0 | 0 | 지상 4층 | 상위 레벨: 지상 5층 | no | 구조체 면:외부 | 4100 | yes | 보강 철근 피복 1 <25 mm> | 교좌장치 | 보강 철근 피복 1 <25 mm> | 5700.01 | 21.59
2820715 | 지상 4층 | 3950 | 6499.91 | 1.29998 | 5.13493 | 25.6746 | 24.6346 | 4.92693 | yes | 0 | 0 | 지상 4층 | 상위 레벨: 지상 5층 | no | 구조체 면:외부 | 4100 | yes | 보강 철근 피복 1 <25 mm> | 교좌장치 | 보강 철근 피복 1 <25 mm> | 6699.91 | 24.6346
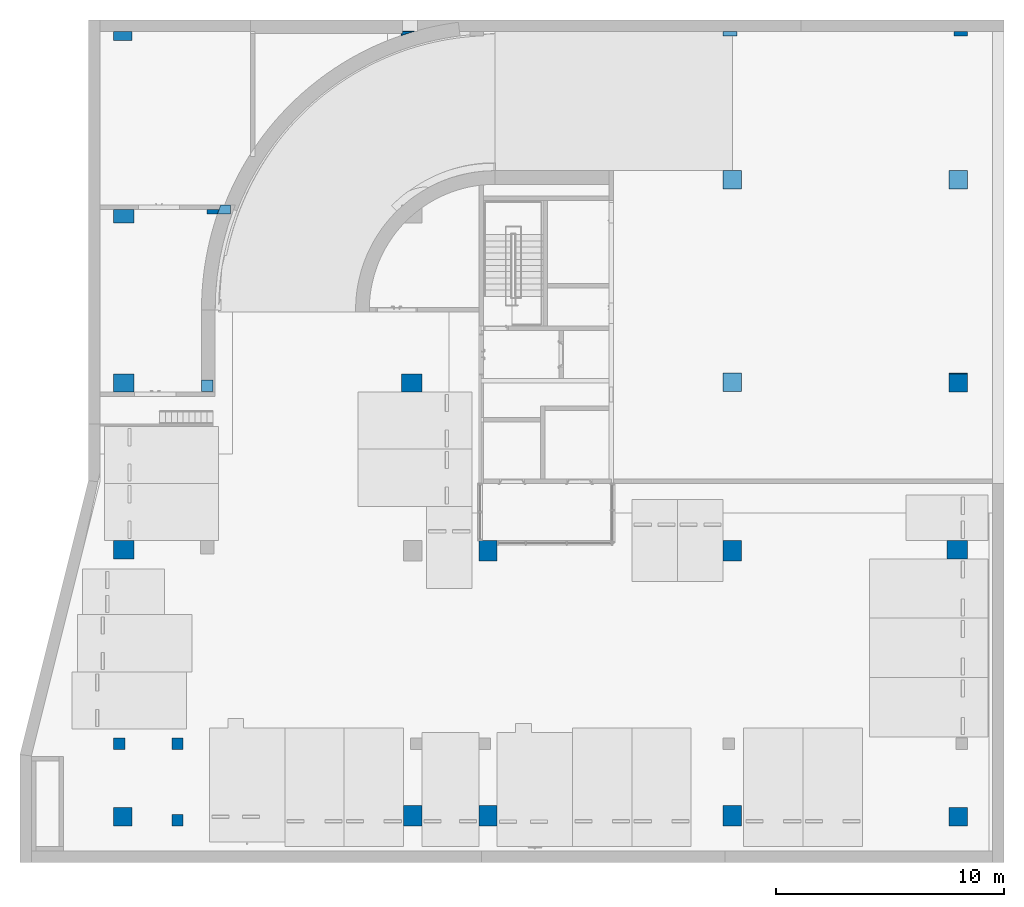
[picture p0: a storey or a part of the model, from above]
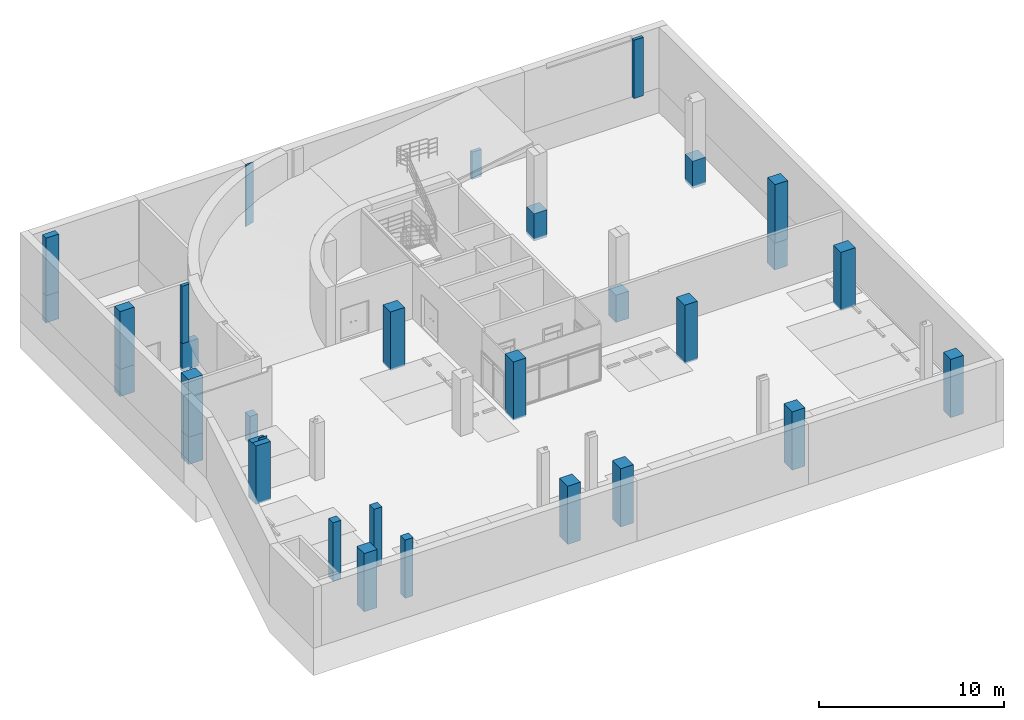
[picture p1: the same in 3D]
Properties of the parts of a building model (IFC2X3), part 38 of 39

# IfcWallStandardCase: 기본 벽:WA111-철근콘크리트구조 벽 200mm_CW1 (252)
Name (기본 벽:WA111-철근콘크리트구조 벽 200mm_CW1:...) | In | Height (mm) | Length (mm) | GrossFootprintArea (m2) | GrossVolume (m3) | GrossSideArea (m2) | NetSideArea (m2) | NetVolume (m3) = 체적 (m3) | 연관 있음 | 베이스 간격띄우기 (mm) | 상단 간격띄우기 (mm) | 베이스 구속조건 | 상단 구속조건 | 상단이 부착됩니다. = ExtendToStructure | 위치선 | 미연결 높이 (mm) | 구조 = LoadBearing | 보강 철근 피복 - 다른 면 | 구조적 용도 | 보강 철근 피복 - 내부 면 = 보강 철근 피복 - 외부 면 | 길이 (mm) | 면적 (m2)
2820717 | 지상 4층 | 3950 | 2800 | 0.56 | 2.212 | 11.06 | 7.28 | 1.456 | yes | 0 | 0 | 지상 4층 | 상위 레벨: 지상 5층 | no | 구조체 면:외부 | 4100 | yes | 보강 철근 피복 1 <25 mm> | 교좌장치 | 보강 철근 피복 1 <25 mm> | 2800 | 7.28
2820719 | 지상 4층 | 3950 | 6700 | 1.34 | 5.293 | 26.465 | 26.075 | 5.215 | yes | 0 | 0 | 지상 4층 | 상위 레벨: 지상 5층 | no | 구조체 면:외부 | 4100 | yes | 보강 철근 피복 1 <25 mm> | 교좌장치 | 보강 철근 피복 1 <25 mm> | 6700 | 26.075
2820721 | 지상 4층 | 4100 | 2800 | 0.56 | 2.296 | 11.48 | 11.09 | 2.218 | yes | 0 | 0 | 지상 4층 | 상위 레벨: 지상 5층 | no | 구조체 면:외부 | 4100 | yes | 보강 철근 피복 1 <25 mm> | 교좌장치 | 보강 철근 피복 1 <25 mm> | 2800 | 11.09
2820723 | 지상 4층 | 4100 | 6700 | 1.34 | 5.359 | 26.795 | 26.795 | 5.359 | yes | 0 | 0 | 지상 4층 | 상위 레벨: 지상 5층 | no | 구조체 면:외부 | 4100 | yes | 보강 철근 피복 1 <25 mm> | 교좌장치 | 보강 철근 피복 1 <25 mm> | 6700 | 26.795
2820725 | 지상 4층 | 4100 | 2600 | 0.52 | 2.132 | 10.66 | 10.66 | 2.132 | yes | 0 | 0 | 지상 4층 | 상위 레벨: 지상 5층 | no | 구조체 면:외부 | 4100 | yes | 보강 철근 피복 1 <25 mm> | 교좌장치 | 보강 철근 피복 1 <25 mm> | 2800 | 10.66
2820727 | 지상 4층 | 3950 | 4400 | 0.88 | 3.476 | 17.38 | 15.28 | 3.056 | yes | 0 | 0 | 지상 4층 | 상위 레벨: 지상 5층 | no | 구조체 면:외부 | 4100 | yes | 보강 철근 피복 1 <25 mm> | 교좌장치 | 보강 철근 피복 1 <25 mm> | 4600 | 15.28
2820729 | 지상 4층 | 4100 | 4300 | 0.86 | 3.475 | 17.375 | 14.85 | 2.97 | yes | 0 | 0 | 지상 4층 | 상위 레벨: 지상 5층 | no | 구조체 면:외부 | 4100 | yes | 보강 철근 피복 1 <25 mm> | 교좌장치 | 보강 철근 피복 1 <25 mm> | 4500 | 14.85
2820731 | 지상 4층 | 3950 | 5990 | 1.198 | 4.7321 | 23.6605 | 23.6605 | 4.7321 | yes | 0 | 0 | 지상 4층 | 상위 레벨: 지상 5층 | no | 구조체 면:외부 | 4100 | yes | 보강 철근 피복 1 <25 mm> | 교좌장치 | 보강 철근 피복 1 <25 mm> | 6090 | 23.6605
2821193 | 지상 5층 | 4100 | 6200 | 1.24 | 4.764 | 23.82 | 22.86 | 4.572 | yes | 0 | 0 | 지상 5층 | 상위 레벨: 지상 6층 | no | 구조체 면:외부 | 4100 | yes | 보강 철근 피복 1 <25 mm> | 교좌장치 | 보강 철근 피복 1 <25 mm> | 6200 | 22.86
2821197 | 지상 5층 | 3950 | 5700.01 | 1.14 | 4.50301 | 22.515 | 16.905 | 3.38101 | yes | 0 | 0 | 지상 5층 | 상위 레벨: 지상 6층 | no | 구조체 면:외부 | 4100 | yes | 보강 철근 피복 1 <25 mm> | 교좌장치 | 보강 철근 피복 1 <25 mm> | 5700.01 | 16.905
2821199 | 지상 5층 | 4100 | 5700 | 1.14 | 4.668 | 23.34 | 21.24 | 4.16551 | yes | 0 | 0 | 지상 5층 | 상위 레벨: 지상 6층 | no | 구조체 면:외부 | 4100 | yes | 보강 철근 피복 1 <25 mm> | 교좌장치 | 보강 철근 피복 1 <25 mm> | 5700 | 21.24
2821201 | 지상 5층 | 4100 | 5500 | 1.1 | 4.51 | 22.55 | 22.55 | 4.51 | yes | 0 | 0 | 지상 5층 | 상위 레벨: 지상 6층 | no | 구조체 면:외부 | 4100 | yes | 보강 철근 피복 1 <25 mm> | 교좌장치 | 보강 철근 피복 1 <25 mm> | 5700 | 22.55
2821205 | 지상 5층 | 4100 | 3203.91 | 0.640782 | 2.62721 | 13.136 | 13.136 | 2.62721 | yes | 0 | 0 | 지상 5층 | 상위 레벨: 지상 6층 | no | 구조체 면:외부 | 4100 | yes | 보강 철근 피복 1 <25 mm> | 교좌장치 | 보강 철근 피복 1 <25 mm> | 3203.91 | 13.136
2821207 | 지상 5층 | 4100 | 2800 | 0.56 | 2.296 | 11.48 | 11.48 | 2.296 | yes | 0 | 0 | 지상 5층 | 상위 레벨: 지상 6층 | no | 구조체 면:외부 | 4100 | yes | 보강 철근 피복 1 <25 mm> | 교좌장치 | 보강 철근 피복 1 <25 mm> | 3000 | 11.48
2821209 | 지상 5층 | 4100 | 2500.01 | 0.500002 | 2.05001 | 10.25 | 10.25 | 2.05001 | yes | 0 | 0 | 지상 5층 | 상위 레벨: 지상 6층 | no | 구조체 면:외부 | 4100 | yes | 보강 철근 피복 1 <25 mm> | 교좌장치 | 보강 철근 피복 1 <25 mm> | 2700.01 | 10.25
2821211 | 지상 5층 | 4100 | 5500.01 | 1.1 | 4.40501 | 22.025 | 21.065 | 4.21301 | yes | 0 | 0 | 지상 5층 | 상위 레벨: 지상 6층 | no | 구조체 면:외부 | 4100 | yes | 보강 철근 피복 1 <25 mm> | 교좌장치 | 보강 철근 피복 1 <25 mm> | 5700.01 | 21.065
2821217 | 지상 5층 | 3950 | 6503.91 | 1.30078 | 5.13809 | 25.6904 | 24.6504 | 4.93009 | yes | 0 | 0 | 지상 5층 | 상위 레벨: 지상 6층 | no | 구조체 면:외부 | 4100 | yes | 보강 철근 피복 1 <25 mm> | 교좌장치 | 보강 철근 피복 1 <25 mm> | 6703.91 | 24.6504
2821219 | 지상 5층 | 3950 | 2800 | 0.56 | 2.212 | 11.06 | 7.28 | 1.456 | yes | 0 | 0 | 지상 5층 | 상위 레벨: 지상 6층 | no | 구조체 면:외부 | 4100 | yes | 보강 철근 피복 1 <25 mm> | 교좌장치 | 보강 철근 피복 1 <25 mm> | 2800 | 7.28
2821221 | 지상 5층 | 3950 | 6700 | 1.34 | 5.293 | 26.465 | 26.075 | 5.215 | yes | 0 | 0 | 지상 5층 | 상위 레벨: 지상 6층 | no | 구조체 면:외부 | 4100 | yes | 보강 철근 피복 1 <25 mm> | 교좌장치 | 보강 철근 피복 1 <25 mm> | 6700 | 26.075
2821223 | 지상 5층 | 4100 | 2800 | 0.56 | 2.296 | 11.48 | 11.09 | 2.218 | yes | 0 | 0 | 지상 5층 | 상위 레벨: 지상 6층 | no | 구조체 면:외부 | 4100 | yes | 보강 철근 피복 1 <25 mm> | 교좌장치 | 보강 철근 피복 1 <25 mm> | 2800 | 11.09
2821225 | 지상 5층 | 4100 | 6700 | 1.34 | 5.494 | 27.47 | 27.47 | 5.494 | yes | 0 | 0 | 지상 5층 | 상위 레벨: 지상 6층 | no | 구조체 면:외부 | 4100 | yes | 보강 철근 피복 1 <25 mm> | 교좌장치 | 보강 철근 피복 1 <25 mm> | 6700 | 27.47
2821227 | 지상 5층 | 4100 | 2600 | 0.52 | 2.132 | 10.66 | 10.66 | 2.132 | yes | 0 | 0 | 지상 5층 | 상위 레벨: 지상 6층 | no | 구조체 면:외부 | 4100 | yes | 보강 철근 피복 1 <25 mm> | 교좌장치 | 보강 철근 피복 1 <25 mm> | 2800 | 10.66
2821229 | 지상 5층 | 3950 | 4400 | 0.88 | 3.476 | 17.38 | 15.28 | 3.056 | yes | 0 | 0 | 지상 5층 | 상위 레벨: 지상 6층 | no | 구조체 면:외부 | 4100 | yes | 보강 철근 피복 1 <25 mm> | 교좌장치 | 보강 철근 피복 1 <25 mm> | 4600 | 15.28
2821231 | 지상 5층 | 4100 | 4300 | 0.86 | 3.475 | 17.375 | 14.749 | 2.9498 | yes | 0 | 0 | 지상 5층 | 상위 레벨: 지상 6층 | no | 구조체 면:외부 | 4100 | yes | 보강 철근 피복 1 <25 mm> | 교좌장치 | 보강 철근 피복 1 <25 mm> | 4500 | 14.749
2821233 | 지상 5층 | 3950 | 6100 | 1.22 | 4.819 | 24.095 | 24.095 | 4.819 | yes | 0 | 0 | 지상 5층 | 상위 레벨: 지상 6층 | no | 구조체 면:외부 | 4100 | yes | 보강 철근 피복 1 <25 mm> | 교좌장치 | 보강 철근 피복 1 <25 mm> | 6200 | 24.095
2821453 | 지상 6층 | 4100 | 6200 | 1.24 | 4.764 | 23.82 | 22.86 | 4.572 | yes | 0 | 0 | 지상 6층 | 상위 레벨: 지상 7층 | no | 구조체 면:외부 | 4100 | yes | 보강 철근 피복 1 <25 mm> | 교좌장치 | 보강 철근 피복 1 <25 mm> | 6200 | 22.86
2821457 | 지상 6층 | 3950 | 5700.01 | 1.14 | 4.50301 | 22.515 | 16.905 | 3.38101 | yes | 0 | 0 | 지상 6층 | 상위 레벨: 지상 7층 | no | 구조체 면:외부 | 4100 | yes | 보강 철근 피복 1 <25 mm> | 교좌장치 | 보강 철근 피복 1 <25 mm> | 5700.01 | 16.905
2821461 | 지상 6층 | 4100 | 5500 | 1.1 | 4.51 | 22.55 | 22.55 | 4.51 | yes | 0 | 0 | 지상 6층 | 상위 레벨: 지상 7층 | no | 구조체 면:외부 | 4100 | yes | 보강 철근 피복 1 <25 mm> | 교좌장치 | 보강 철근 피복 1 <25 mm> | 5700 | 22.55
2821465 | 지상 6층 | 4100 | 3300 | 0.66 | 2.706 | 13.53 | 13.53 | 2.706 | yes | 0 | 0 | 지상 6층 | 상위 레벨: 지상 7층 | no | 구조체 면:외부 | 4100 | yes | 보강 철근 피복 1 <25 mm> | 교좌장치 | 보강 철근 피복 1 <25 mm> | 3400 | 13.53
2821467 | 지상 6층 | 4100 | 2800 | 0.56 | 2.296 | 11.48 | 11.48 | 2.296 | yes | 0 | 0 | 지상 6층 | 상위 레벨: 지상 7층 | no | 구조체 면:외부 | 4100 | yes | 보강 철근 피복 1 <25 mm> | 교좌장치 | 보강 철근 피복 1 <25 mm> | 3000 | 11.48
2821469 | 지상 6층 | 4100 | 2500.01 | 0.500002 | 2.05001 | 10.25 | 10.25 | 2.05001 | yes | 0 | 0 | 지상 6층 | 상위 레벨: 지상 7층 | no | 구조체 면:외부 | 4100 | yes | 보강 철근 피복 1 <25 mm> | 교좌장치 | 보강 철근 피복 1 <25 mm> | 2700.01 | 10.25
2821471 | 지상 6층 | 4100 | 5500.01 | 1.1 | 4.40501 | 22.025 | 21.065 | 4.21301 | yes | 0 | 0 | 지상 6층 | 상위 레벨: 지상 7층 | no | 구조체 면:외부 | 4100 | yes | 보강 철근 피복 1 <25 mm> | 교좌장치 | 보강 철근 피복 1 <25 mm> | 5700.01 | 21.065
2821477 | 지상 6층 | 3950 | 6503.91 | 1.30078 | 5.13809 | 25.6904 | 24.6504 | 4.93009 | yes | 0 | 0 | 지상 6층 | 상위 레벨: 지상 7층 | no | 구조체 면:외부 | 4100 | yes | 보강 철근 피복 1 <25 mm> | 교좌장치 | 보강 철근 피복 1 <25 mm> | 6703.91 | 24.6504
2821479 | 지상 6층 | 3950 | 2800 | 0.56 | 1.4272 | 7.136 | 7.136 | 1.4272 | yes | 0 | 0 | 지상 6층 | 상위 레벨: 지상 7층 | no | 구조체 면:외부 | 4100 | yes | 보강 철근 피복 1 <25 mm> | 교좌장치 | 보강 철근 피복 1 <25 mm> | 2800 | 7.136
2821481 | 지상 6층 | 3950 | 6700 | 1.34 | 5.293 | 26.465 | 26.075 | 5.215 | yes | 0 | 0 | 지상 6층 | 상위 레벨: 지상 7층 | no | 구조체 면:외부 | 4100 | yes | 보강 철근 피복 1 <25 mm> | 교좌장치 | 보강 철근 피복 1 <25 mm> | 6700 | 26.075
2821483 | 지상 6층 | 4100 | 2800 | 0.56 | 2.296 | 11.48 | 11.09 | 2.218 | yes | 0 | 0 | 지상 6층 | 상위 레벨: 지상 7층 | no | 구조체 면:외부 | 4100 | yes | 보강 철근 피복 1 <25 mm> | 교좌장치 | 보강 철근 피복 1 <25 mm> | 2800 | 11.09
2821485 | 지상 6층 | 4100 | 6700 | 1.34 | 5.494 | 27.47 | 27.47 | 5.494 | yes | 0 | 0 | 지상 6층 | 상위 레벨: 지상 7층 | no | 구조체 면:외부 | 4100 | yes | 보강 철근 피복 1 <25 mm> | 교좌장치 | 보강 철근 피복 1 <25 mm> | 6700 | 27.47
2821487 | 지상 6층 | 4100 | 2600 | 0.52 | 2.132 | 10.66 | 10.66 | 2.132 | yes | 0 | 0 | 지상 6층 | 상위 레벨: 지상 7층 | no | 구조체 면:외부 | 4100 | yes | 보강 철근 피복 1 <25 mm> | 교좌장치 | 보강 철근 피복 1 <25 mm> | 2800 | 10.66
2821489 | 지상 6층 | 3950 | 4400 | 0.88 | 3.0416 | 15.208 | 15.208 | 3.0416 | yes | 0 | 0 | 지상 6층 | 상위 레벨: 지상 7층 | no | 구조체 면:외부 | 4100 | yes | 보강 철근 피복 1 <25 mm> | 교좌장치 | 보강 철근 피복 1 <25 mm> | 4600 | 15.208
2821491 | 지상 6층 | 4100 | 4300 | 0.86 | 3.475 | 17.375 | 14.749 | 2.9498 | yes | 0 | 0 | 지상 6층 | 상위 레벨: 지상 7층 | no | 구조체 면:외부 | 4100 | yes | 보강 철근 피복 1 <25 mm> | 교좌장치 | 보강 철근 피복 1 <25 mm> | 4500 | 14.749
2821493 | 지상 6층 | 3950 | 6100 | 1.22 | 4.819 | 24.095 | 24.095 | 4.819 | yes | 0 | 0 | 지상 6층 | 상위 레벨: 지상 7층 | no | 구조체 면:외부 | 4100 | yes | 보강 철근 피복 1 <25 mm> | 교좌장치 | 보강 철근 피복 1 <25 mm> | 6200 | 24.095
2821649 | 지상 7층 | 4100 | 6200 | 1.24 | 4.764 | 23.82 | 22.86 | 4.572 | yes | 0 | 0 | 지상 7층 | 상위 레벨: 지상 8층 | no | 구조체 면:외부 | 4100 | yes | 보강 철근 피복 1 <25 mm> | 교좌장치 | 보강 철근 피복 1 <25 mm> | 6200 | 22.86
2821651 | 지상 7층 | 4100 | 12503.9 | 2.50078 | 10.2532 | 51.266 | 46.026 | 9.20521 | yes | 0 | 0 | 지상 7층 | 상위 레벨: 지상 8층 | no | 구조체 면:외부 | 4100 | yes | 보강 철근 피복 1 <25 mm> | 교좌장치 | 보강 철근 피복 1 <25 mm> | 12403.9 | 46.026
2821653 | 지상 7층 | 3950 | 5700.01 | 1.14 | 4.50301 | 22.515 | 16.905 | 3.38101 | yes | 0 | 0 | 지상 7층 | 상위 레벨: 지상 8층 | no | 구조체 면:외부 | 4100 | yes | 보강 철근 피복 1 <25 mm> | 교좌장치 | 보강 철근 피복 1 <25 mm> | 5700.01 | 16.905
2821655 | 지상 7층 | 4100 | 5700 | 1.14 | 4.558 | 22.79 | 20.69 | 4.083 | yes | 0 | 0 | 지상 7층 | 상위 레벨: 지상 8층 | no | 구조체 면:외부 | 4100 | yes | 보강 철근 피복 1 <25 mm> | 교좌장치 | 보강 철근 피복 1 <25 mm> | 5700 | 20.415
2821657 | 지상 7층 | 4100 | 5500 | 1.1 | 4.51 | 22.55 | 22.55 | 4.51 | yes | 0 | 0 | 지상 7층 | 상위 레벨: 지상 8층 | no | 구조체 면:외부 | 4100 | yes | 보강 철근 피복 1 <25 mm> | 교좌장치 | 보강 철근 피복 1 <25 mm> | 5700 | 22.55
2821661 | 지상 7층 | 4100 | 3203.91 | 0.640782 | 2.62721 | 13.136 | 13.136 | 2.62721 | yes | 0 | 0 | 지상 7층 | 상위 레벨: 지상 8층 | no | 구조체 면:외부 | 4100 | yes | 보강 철근 피복 1 <25 mm> | 교좌장치 | 보강 철근 피복 1 <25 mm> | 3203.91 | 13.136
2821663 | 지상 7층 | 4100 | 2800 | 0.56 | 2.296 | 11.48 | 11.48 | 2.296 | yes | 0 | 0 | 지상 7층 | 상위 레벨: 지상 8층 | no | 구조체 면:외부 | 4100 | yes | 보강 철근 피복 1 <25 mm> | 교좌장치 | 보강 철근 피복 1 <25 mm> | 3000 | 11.48
2821665 | 지상 7층 | 4100 | 2500.01 | 0.500002 | 2.05001 | 10.25 | 10.25 | 2.05001 | yes | 0 | 0 | 지상 7층 | 상위 레벨: 지상 8층 | no | 구조체 면:외부 | 4100 | yes | 보강 철근 피복 1 <25 mm> | 교좌장치 | 보강 철근 피복 1 <25 mm> | 2700.01 | 10.25
2821667 | 지상 7층 | 4100 | 5500.01 | 1.1 | 4.40501 | 22.025 | 21.065 | 4.21301 | yes | 0 | 0 | 지상 7층 | 상위 레벨: 지상 8층 | no | 구조체 면:외부 | 4100 | yes | 보강 철근 피복 1 <25 mm> | 교좌장치 | 보강 철근 피복 1 <25 mm> | 5700.01 | 21.065
2821673 | 지상 7층 | 3950 | 6503.91 | 1.30078 | 5.13809 | 25.6904 | 24.6504 | 4.93009 | yes | 0 | 0 | 지상 7층 | 상위 레벨: 지상 8층 | no | 구조체 면:외부 | 4100 | yes | 보강 철근 피복 1 <25 mm> | 교좌장치 | 보강 철근 피복 1 <25 mm> | 6703.91 | 24.6504
2821675 | 지상 7층 | 3950 | 2800 | 0.56 | 2.212 | 11.06 | 7.28 | 1.456 | yes | 0 | 0 | 지상 7층 | 상위 레벨: 지상 8층 | no | 구조체 면:외부 | 4100 | yes | 보강 철근 피복 1 <25 mm> | 교좌장치 | 보강 철근 피복 1 <25 mm> | 2800 | 7.28
2821677 | 지상 7층 | 3950 | 6700 | 1.34 | 5.293 | 26.465 | 26.075 | 5.215 | yes | 0 | 0 | 지상 7층 | 상위 레벨: 지상 8층 | no | 구조체 면:외부 | 4100 | yes | 보강 철근 피복 1 <25 mm> | 교좌장치 | 보강 철근 피복 1 <25 mm> | 6700 | 26.075
2821679 | 지상 7층 | 4100 | 2800 | 0.56 | 2.296 | 11.48 | 11.09 | 2.218 | yes | 0 | 0 | 지상 7층 | 상위 레벨: 지상 8층 | no | 구조체 면:외부 | 4100 | yes | 보강 철근 피복 1 <25 mm> | 교좌장치 | 보강 철근 피복 1 <25 mm> | 2800 | 11.09
2821681 | 지상 7층 | 4100 | 6700 | 1.34 | 5.359 | 26.795 | 26.795 | 5.359 | yes | 0 | 0 | 지상 7층 | 상위 레벨: 지상 8층 | no | 구조체 면:외부 | 4100 | yes | 보강 철근 피복 1 <25 mm> | 교좌장치 | 보강 철근 피복 1 <25 mm> | 6700 | 26.795
2821683 | 지상 7층 | 4100 | 2600 | 0.52 | 2.132 | 10.66 | 10.66 | 2.132 | yes | 0 | 0 | 지상 7층 | 상위 레벨: 지상 8층 | no | 구조체 면:외부 | 4100 | yes | 보강 철근 피복 1 <25 mm> | 교좌장치 | 보강 철근 피복 1 <25 mm> | 2800 | 10.66
2821685 | 지상 7층 | 3950 | 4400 | 0.88 | 3.476 | 17.38 | 15.28 | 3.056 | yes | 0 | 0 | 지상 7층 | 상위 레벨: 지상 8층 | no | 구조체 면:외부 | 4100 | yes | 보강 철근 피복 1 <25 mm> | 교좌장치 | 보강 철근 피복 1 <25 mm> | 4600 | 15.28
2821687 | 지상 7층 | 4100 | 4300 | 0.86 | 3.475 | 17.375 | 14.749 | 2.9498 | yes | 0 | 0 | 지상 7층 | 상위 레벨: 지상 8층 | no | 구조체 면:외부 | 4100 | yes | 보강 철근 피복 1 <25 mm> | 교좌장치 | 보강 철근 피복 1 <25 mm> | 4500 | 14.749
2821689 | 지상 7층 | 3950 | 6100 | 1.22 | 4.819 | 24.095 | 24.095 | 4.819 | yes | 0 | 0 | 지상 7층 | 상위 레벨: 지상 8층 | no | 구조체 면:외부 | 4100 | yes | 보강 철근 피복 1 <25 mm> | 교좌장치 | 보강 철근 피복 1 <25 mm> | 6200 | 24.095
2821995 | 지상 8층 | 4100 | 6200 | 1.24 | 4.764 | 23.82 | 22.86 | 4.572 | yes | 0 | 0 | 지상 8층 | 상위 레벨: 지상 9층 | no | 구조체 면:외부 | 4100 | yes | 보강 철근 피복 1 <25 mm> | 교좌장치 | 보강 철근 피복 1 <25 mm> | 6200 | 22.86
2821999 | 지상 8층 | 3950 | 5700.01 | 1.14 | 4.50301 | 22.515 | 16.905 | 3.38101 | yes | 0 | 0 | 지상 8층 | 상위 레벨: 지상 9층 | no | 구조체 면:외부 | 4100 | yes | 보강 철근 피복 1 <25 mm> | 교좌장치 | 보강 철근 피복 1 <25 mm> | 5700.01 | 16.905
2822001 | 지상 8층 | 4100 | 5700 | 1.14 | 4.668 | 23.34 | 21.24 | 4.16551 | yes | 0 | 0 | 지상 8층 | 상위 레벨: 지상 9층 | no | 구조체 면:외부 | 4100 | yes | 보강 철근 피복 1 <25 mm> | 교좌장치 | 보강 철근 피복 1 <25 mm> | 5700 | 21.24
2822003 | 지상 8층 | 4100 | 5500 | 1.1 | 4.51 | 22.55 | 22.55 | 4.51 | yes | 0 | 0 | 지상 8층 | 상위 레벨: 지상 9층 | no | 구조체 면:외부 | 4100 | yes | 보강 철근 피복 1 <25 mm> | 교좌장치 | 보강 철근 피복 1 <25 mm> | 5700 | 22.55
2822007 | 지상 8층 | 4100 | 3203.91 | 0.640782 | 2.62721 | 13.136 | 13.136 | 2.62721 | yes | 0 | 0 | 지상 8층 | 상위 레벨: 지상 9층 | no | 구조체 면:외부 | 4100 | yes | 보강 철근 피복 1 <25 mm> | 교좌장치 | 보강 철근 피복 1 <25 mm> | 3203.91 | 13.136
2822009 | 지상 8층 | 4100 | 2800 | 0.56 | 2.296 | 11.48 | 11.48 | 2.296 | yes | 0 | 0 | 지상 8층 | 상위 레벨: 지상 9층 | no | 구조체 면:외부 | 4100 | yes | 보강 철근 피복 1 <25 mm> | 교좌장치 | 보강 철근 피복 1 <25 mm> | 3000 | 11.48
2822011 | 지상 8층 | 4100 | 2500.01 | 0.500002 | 2.05001 | 10.25 | 10.25 | 2.05001 | yes | 0 | 0 | 지상 8층 | 상위 레벨: 지상 9층 | no | 구조체 면:외부 | 4100 | yes | 보강 철근 피복 1 <25 mm> | 교좌장치 | 보강 철근 피복 1 <25 mm> | 2700.01 | 10.25
2822013 | 지상 8층 | 4100 | 5500.01 | 1.1 | 4.40501 | 22.025 | 21.065 | 4.21301 | yes | 0 | 0 | 지상 8층 | 상위 레벨: 지상 9층 | no | 구조체 면:외부 | 4100 | yes | 보강 철근 피복 1 <25 mm> | 교좌장치 | 보강 철근 피복 1 <25 mm> | 5700.01 | 21.065
2822019 | 지상 8층 | 3950 | 6503.91 | 1.30078 | 5.13809 | 25.6904 | 24.6504 | 4.93009 | yes | 0 | 0 | 지상 8층 | 상위 레벨: 지상 9층 | no | 구조체 면:외부 | 4100 | yes | 보강 철근 피복 1 <25 mm> | 교좌장치 | 보강 철근 피복 1 <25 mm> | 6703.91 | 24.6504
2822021 | 지상 8층 | 3950 | 2800 | 0.56 | 2.212 | 11.06 | 7.28 | 1.456 | yes | 0 | 0 | 지상 8층 | 상위 레벨: 지상 9층 | no | 구조체 면:외부 | 4100 | yes | 보강 철근 피복 1 <25 mm> | 교좌장치 | 보강 철근 피복 1 <25 mm> | 2800 | 7.28
2822023 | 지상 8층 | 3950 | 6700 | 1.34 | 5.293 | 26.465 | 26.075 | 5.215 | yes | 0 | 0 | 지상 8층 | 상위 레벨: 지상 9층 | no | 구조체 면:외부 | 4100 | yes | 보강 철근 피복 1 <25 mm> | 교좌장치 | 보강 철근 피복 1 <25 mm> | 6700 | 26.075
2822025 | 지상 8층 | 4100 | 2800 | 0.56 | 2.296 | 11.48 | 11.09 | 2.218 | yes | 0 | 0 | 지상 8층 | 상위 레벨: 지상 9층 | no | 구조체 면:외부 | 4100 | yes | 보강 철근 피복 1 <25 mm> | 교좌장치 | 보강 철근 피복 1 <25 mm> | 2800 | 11.09
2822027 | 지상 8층 | 4100 | 6700 | 1.34 | 5.494 | 27.47 | 27.47 | 5.494 | yes | 0 | 0 | 지상 8층 | 상위 레벨: 지상 9층 | no | 구조체 면:외부 | 4100 | yes | 보강 철근 피복 1 <25 mm> | 교좌장치 | 보강 철근 피복 1 <25 mm> | 6700 | 27.47
2822029 | 지상 8층 | 4100 | 2600 | 0.52 | 2.132 | 10.66 | 10.66 | 2.132 | yes | 0 | 0 | 지상 8층 | 상위 레벨: 지상 9층 | no | 구조체 면:외부 | 4100 | yes | 보강 철근 피복 1 <25 mm> | 교좌장치 | 보강 철근 피복 1 <25 mm> | 2800 | 10.66
2822031 | 지상 8층 | 3950 | 4400 | 0.88 | 3.476 | 17.38 | 15.28 | 3.056 | yes | 0 | 0 | 지상 8층 | 상위 레벨: 지상 9층 | no | 구조체 면:외부 | 4100 | yes | 보강 철근 피복 1 <25 mm> | 교좌장치 | 보강 철근 피복 1 <25 mm> | 4600 | 15.28
2822033 | 지상 8층 | 4100 | 4300 | 0.86 | 3.475 | 17.375 | 14.749 | 2.9498 | yes | 0 | 0 | 지상 8층 | 상위 레벨: 지상 9층 | no | 구조체 면:외부 | 4100 | yes | 보강 철근 피복 1 <25 mm> | 교좌장치 | 보강 철근 피복 1 <25 mm> | 4500 | 14.749
2822035 | 지상 8층 | 3950 | 6100 | 1.22 | 4.819 | 24.095 | 24.095 | 4.819 | yes | 0 | 0 | 지상 8층 | 상위 레벨: 지상 9층 | no | 구조체 면:외부 | 4100 | yes | 보강 철근 피복 1 <25 mm> | 교좌장치 | 보강 철근 피복 1 <25 mm> | 6200 | 24.095
2822201 | 지상 9층 | 4500 | 6200 | 1.24 | 5.25716 | 26.2858 | 25.3258 | 5.06516 | yes | 0 | 0 | 지상 9층 | 상위 레벨: 지상 10층 | no | 구조체 면:외부 | 4500 | yes | 보강 철근 피복 1 <25 mm> | 교좌장치 | 보강 철근 피복 1 <25 mm> | 6200 | 25.3258
2822203 | 지상 9층 | 4350 | 12503.9 | 2.50078 | 10.8784 | 54.392 | 49.152 | 9.8304 | yes | 0 | 0 | 지상 9층 | 상위 레벨: 지상 10층 | no | 구조체 면:외부 | 4500 | yes | 보강 철근 피복 1 <25 mm> | 교좌장치 | 보강 철근 피복 1 <25 mm> | 12403.9 | 49.152
2822205 | 지상 9층 | 4350 | 5700.01 | 1.14 | 4.95901 | 24.795 | 19.185 | 3.83701 | yes | 0 | 0 | 지상 9층 | 상위 레벨: 지상 10층 | no | 구조체 면:외부 | 4500 | yes | 보강 철근 피복 1 <25 mm> | 교좌장치 | 보강 철근 피복 1 <25 mm> | 5700.01 | 19.185
2822209 | 지상 9층 | 4500 | 5500 | 1.1 | 4.95 | 24.75 | 24.75 | 4.95 | yes | 0 | 0 | 지상 9층 | 상위 레벨: 지상 10층 | no | 구조체 면:외부 | 4500 | yes | 보강 철근 피복 1 <25 mm> | 교좌장치 | 보강 철근 피복 1 <25 mm> | 5700 | 24.75
2822213 | 지상 9층 | 4500 | 3203.91 | 0.640782 | 2.88352 | 14.4176 | 14.4176 | 2.88352 | yes | 0 | 0 | 지상 9층 | 상위 레벨: 지상 10층 | no | 구조체 면:외부 | 4500 | yes | 보강 철근 피복 1 <25 mm> | 교좌장치 | 보강 철근 피복 1 <25 mm> | 3203.91 | 14.4176
2822215 | 지상 9층 | 4500 | 2800 | 0.56 | 2.52 | 12.6 | 12.6 | 2.52 | yes | 0 | 0 | 지상 9층 | 상위 레벨: 지상 10층 | no | 구조체 면:외부 | 4500 | yes | 보강 철근 피복 1 <25 mm> | 교좌장치 | 보강 철근 피복 1 <25 mm> | 3000 | 12.6
2822217 | 지상 9층 | 4500 | 2500.01 | 0.500002 | 2.25001 | 11.25 | 11.25 | 2.25001 | yes | 0 | 0 | 지상 9층 | 상위 레벨: 지상 10층 | no | 구조체 면:외부 | 4500 | yes | 보강 철근 피복 1 <25 mm> | 교좌장치 | 보강 철근 피복 1 <25 mm> | 2700.01 | 11.25
2822219 | 지상 9층 | 4500 | 5500.01 | 1.1 | 4.84501 | 24.225 | 23.265 | 4.65301 | yes | 0 | 0 | 지상 9층 | 상위 레벨: 지상 10층 | no | 구조체 면:외부 | 4500 | yes | 보강 철근 피복 1 <25 mm> | 교좌장치 | 보강 철근 피복 1 <25 mm> | 5700.01 | 23.265
2822225 | 지상 9층 | 4350 | 6503.91 | 1.30078 | 5.6584 | 28.292 | 27.252 | 5.4504 | yes | 0 | 0 | 지상 9층 | 상위 레벨: 지상 10층 | no | 구조체 면:외부 | 4500 | yes | 보강 철근 피복 1 <25 mm> | 교좌장치 | 보강 철근 피복 1 <25 mm> | 6703.91 | 27.252
2822227 | 지상 9층 | 4350 | 2800 | 0.56 | 2.436 | 12.18 | 8.4 | 1.68 | yes | 0 | 0 | 지상 9층 | 상위 레벨: 지상 10층 | no | 구조체 면:외부 | 4500 | yes | 보강 철근 피복 1 <25 mm> | 교좌장치 | 보강 철근 피복 1 <25 mm> | 2800 | 8.4
2822229 | 지상 9층 | 4350 | 6700 | 1.34 | 5.829 | 29.145 | 28.755 | 5.751 | yes | 0 | 0 | 지상 9층 | 상위 레벨: 지상 10층 | no | 구조체 면:외부 | 4500 | yes | 보강 철근 피복 1 <25 mm> | 교좌장치 | 보강 철근 피복 1 <25 mm> | 6700 | 28.755
2822231 | 지상 9층 | 4500 | 2800 | 0.56 | 2.52 | 12.6 | 12.21 | 2.442 | yes | 0 | 0 | 지상 9층 | 상위 레벨: 지상 10층 | no | 구조체 면:외부 | 4500 | yes | 보강 철근 피복 1 <25 mm> | 교좌장치 | 보강 철근 피복 1 <25 mm> | 2800 | 12.21
2822233 | 지상 9층 | 4500 | 6700 | 1.34 | 6.03 | 30.15 | 30.15 | 6.03 | yes | 0 | 0 | 지상 9층 | 상위 레벨: 지상 10층 | no | 구조체 면:외부 | 4500 | yes | 보강 철근 피복 1 <25 mm> | 교좌장치 | 보강 철근 피복 1 <25 mm> | 6701.03 | 30.15
2822235 | 지상 9층 | 4500 | 2600 | 0.52 | 2.34 | 11.7 | 11.7 | 2.34 | yes | 0 | 0 | 지상 9층 | 상위 레벨: 지상 10층 | no | 구조체 면:외부 | 4500 | yes | 보강 철근 피복 1 <25 mm> | 교좌장치 | 보강 철근 피복 1 <25 mm> | 2800 | 11.7
2822237 | 지상 9층 | 4350 | 4400 | 0.88 | 3.828 | 19.14 | 17.04 | 3.408 | yes | 0 | 0 | 지상 9층 | 상위 레벨: 지상 10층 | no | 구조체 면:외부 | 4500 | yes | 보강 철근 피복 1 <25 mm> | 교좌장치 | 보강 철근 피복 1 <25 mm> | 4600 | 17.04
2822239 | 지상 9층 | 4500 | 4300 | 0.86 | 3.819 | 19.095 | 16.469 | 3.2938 | yes | 0 | 0 | 지상 9층 | 상위 레벨: 지상 10층 | no | 구조체 면:외부 | 4500 | yes | 보강 철근 피복 1 <25 mm> | 교좌장치 | 보강 철근 피복 1 <25 mm> | 4500 | 16.469
2822241 | 지상 9층 | 4500 | 6090 | 1.218 | 5.481 | 27.405 | 27.405 | 5.481 | yes | 0 | 0 | 지상 9층 | 상위 레벨: 지상 10층 | no | 구조체 면:외부 | 4500 | yes | 보강 철근 피복 1 <25 mm> | 교좌장치 | 보강 철근 피복 1 <25 mm> | 6190 | 27.405
2822421 | 지상 10층 | 5000 | 2581.99 | 0.516398 | 2.58199 | 12.91 | 12.91 | 2.58199 | yes | 0 | 0 | 지상 10층 | 상위 레벨: 옥탑층 | no | 구조체 면:외부 | 5000 | yes | 보강 철근 피복 1 <25 mm> | 교좌장치 | 보강 철근 피복 1 <25 mm> | 2817.99 | 12.91
2822811 | 옥탑층 | 3850 | 3001.85 | 0.600369 | 2.20746 | 11.0373 | 11.0373 | 2.20746 | yes | 0 | 0 | 옥탑층 | 상위 레벨: 지붕층 | yes | 구조체 면:외부 | 4000 | yes | 보강 철근 피복 1 <25 mm> | 교좌장치 | 보강 철근 피복 1 <25 mm> | 2801.85 | 11.0373
2822813 | 옥탑층 | 3850 | 12403.9 | 2.48078 | 9.55101 | 47.7551 | 41.9551 | 8.39101 | yes | 0 | 0 | 옥탑층 | 상위 레벨: 지붕층 | yes | 구조체 면:외부 | 4000 | yes | 보강 철근 피복 1 <25 mm> | 교좌장치 | 보강 철근 피복 1 <25 mm> | 12403.9 | 41.9551
2822819 | 옥탑층 | 3850 | 5500 | 1.1 | 4.235 | 21.175 | 21.175 | 4.235 | yes | 0 | 0 | 옥탑층 | 상위 레벨: 지붕층 | yes | 구조체 면:외부 | 4000 | yes | 보강 철근 피복 1 <25 mm> | 교좌장치 | 보강 철근 피복 1 <25 mm> | 5700 | 21.175
2822821 | 옥탑층 | 3850 | 6201.84 | 1.24037 | 4.77542 | 23.8771 | 22.9171 | 4.58342 | yes | 0 | 0 | 옥탑층 | 상위 레벨: 지붕층 | yes | 구조체 면:외부 | 4000 | yes | 보강 철근 피복 1 <25 mm> | 교좌장치 | 보강 철근 피복 1 <25 mm> | 6301.84 | 22.9171
2822823 | 옥탑층 | 3850 | 3203.91 | 0.640782 | 2.46701 | 12.3351 | 12.3351 | 2.46701 | yes | 0 | 0 | 옥탑층 | 상위 레벨: 지붕층 | yes | 구조체 면:외부 | 4000 | yes | 보강 철근 피복 1 <25 mm> | 교좌장치 | 보강 철근 피복 1 <25 mm> | 3203.91 | 12.3351
2822825 | 옥탑층 | 3850 | 2800 | 0.56 | 2.156 | 10.78 | 10.78 | 2.156 | yes | 0 | 0 | 옥탑층 | 상위 레벨: 지붕층 | yes | 구조체 면:외부 | 4000 | yes | 보강 철근 피복 1 <25 mm> | 교좌장치 | 보강 철근 피복 1 <25 mm> | 3000 | 10.78
2822827 | 옥탑층 | 3850 | 2501.85 | 0.500369 | 1.92642 | 9.63211 | 9.63211 | 1.92642 | yes | 0 | 0 | 옥탑층 | 상위 레벨: 지붕층 | yes | 구조체 면:외부 | 4000 | yes | 보강 철근 피복 1 <25 mm> | 교좌장치 | 보강 철근 피복 1 <25 mm> | 2701.85 | 9.63211
2822829 | 옥탑층 | 3850 | 5501.85 | 1.10037 | 4.23642 | 21.1821 | 21.1821 | 4.23642 | yes | 0 | 0 | 옥탑층 | 상위 레벨: 지붕층 | yes | 구조체 면:외부 | 4000 | yes | 보강 철근 피복 1 <25 mm> | 교좌장치 | 보강 철근 피복 1 <25 mm> | 5701.85 | 21.1821
2822831 | 옥탑층 | 3850 | 2100 | 0.42 | 1.617 | 8.085 | 8.085 | 1.617 | yes | 0 | 0 | 옥탑층 | 상위 레벨: 지붕층 | yes | 구조체 면:외부 | 4000 | yes |  | 교좌장치 | 보강 철근 피복 1 <25 mm> | 2300 | 8.085
2822835 | 옥탑층 | 3850 | 6503.91 | 1.30078 | 5.00801 | 25.0401 | 25.0401 | 5.00801 | yes | 0 | 0 | 옥탑층 | 상위 레벨: 지붕층 | yes | 구조체 면:외부 | 4000 | yes | 보강 철근 피복 1 <25 mm> | 교좌장치 | 보강 철근 피복 1 <25 mm> | 6703.91 | 25.0401
2822839 | 옥탑층 | 3850 | 6503.91 | 1.29731 | 5.00801 | 25.0401 | 22.7301 | 4.5341 | yes | 0 | 0 | 옥탑층 | 상위 레벨: 지붕층 | yes | 구조체 면:외부 | 4000 | yes | 보강 철근 피복 1 <25 mm> | 교좌장치 | 보강 철근 피복 1 <25 mm> | 6703.91 | 22.7301
2822841 | 옥탑층 | 3850 | 4500 | 0.9 | 3.465 | 17.325 | 15.725 | 3.145 | yes | 0 | 0 | 옥탑층 | 상위 레벨: 지붕층 | yes | 구조체 면:외부 | 4000 | yes | 보강 철근 피복 1 <25 mm> | 교좌장치 | 보강 철근 피복 1 <25 mm> | 4400 | 15.725
2822843 | 옥탑층 | 3850 | 6503.91 | 1.30078 | 5.00801 | 25.0401 | 25.0401 | 5.00804 | yes | 0 | 0 | 옥탑층 | 상위 레벨: 지붕층 | yes | 구조체 면:외부 | 4000 | yes | 보강 철근 피복 1 <25 mm> | 교좌장치 | 보강 철근 피복 1 <25 mm> | 6703.91 | 25.0401
2822845 | 옥탑층 | 3850 | 2600 | 0.52 | 2.002 | 10.01 | 10.01 | 2.002 | yes | 0 | 0 | 옥탑층 | 상위 레벨: 지붕층 | yes | 구조체 면:외부 | 4000 | yes | 보강 철근 피복 1 <25 mm> | 교좌장치 | 보강 철근 피복 1 <25 mm> | 2800 | 10.01
2989789 | 옥탑층 | 1300 | 28500 | 5.70001 | 7.41001 | 37.05 | 37.05 | 7.41001 |  | 0 | -2700 | 옥탑층 | 상위 레벨: 지붕층 | no | 벽 중심선 | 1300 | no |  | 비교좌장치 |  | 28500 | 37.05
2989867 | 옥탑층 | 1300 | 37200 | 7.44 | 9.672 | 48.36 | 48.36 | 9.672 |  | 0 | -2700 | 옥탑층 | 상위 레벨: 지붕층 | no | 벽 중심선 | 1300 | no |  | 비교좌장치 |  | 37200 | 48.36
2989951 | 옥탑층 | 1300 | 35000 | 7 | 9.1 | 45.5 | 45.5 | 9.1 |  | 0 | -2700 | 옥탑층 | 상위 레벨: 지붕층 | no | 벽 중심선 | 1300 | no |  | 비교좌장치 |  | 35000 | 45.5
2990042 | 옥탑층 | 1300 | 16000 | 3.2 | 4.16 | 20.8 | 20.8 | 4.16 |  | 0 | -2700 | 옥탑층 | 상위 레벨: 지붕층 | no | 벽 중심선 | 1300 | no |  | 비교좌장치 |  | 16000 | 20.8
2990103 | 옥탑층 | 1300 | 7249.97 | 1.44999 | 1.88499 | 9.42496 | 9.42496 | 1.88499 |  | 0 | -2700 | 옥탑층 | 상위 레벨: 지붕층 | no | 벽 중심선 | 1300 | no |  | 비교좌장치 |  | 7424.97 | 9.42496
2990200 | 옥탑층 | 1300 | 1100 | 0.22 | 0.286 | 1.43 | 1.43 | 0.286 |  | 0 | -2700 | 옥탑층 | 상위 레벨: 지붕층 | no | 벽 중심선 | 1300 | no |  | 비교좌장치 |  | 1100 | 1.43
2990279 | 옥탑층 | 1300 | 5100 | 1.02 | 1.326 | 6.63 | 6.63 | 1.326 |  | 0 | -2700 | 옥탑층 | 상위 레벨: 지붕층 | no | 벽 중심선 | 1300 | no |  | 비교좌장치 |  | 5300 | 6.63
2992261 | 옥탑층 | 700 | 3001.85 | 0.600369 | 0.420259 | 2.10129 | 2.10129 | 0.420259 | yes | 0 | 700 | 지붕층 | 상위 레벨: 지붕층 | no | 구조체 면:외부 | 700 | yes | 보강 철근 피복 1 <25 mm> | 교좌장치 | 보강 철근 피복 1 <25 mm> | 2801.85 | 2.10129
2992263 | 옥탑층 | 700 | 12400 | 2.48 | 1.736 | 8.68 | 8.68 | 1.736 | yes | 0 | 700 | 지붕층 | 상위 레벨: 지붕층 | no | 구조체 면:외부 | 700 | yes | 보강 철근 피복 1 <25 mm> | 교좌장치 | 보강 철근 피복 1 <25 mm> | 12400 | 8.68
2992265 | 옥탑층 | 700 | 10701.8 | 2.14037 | 1.49826 | 7.49129 | 7.49129 | 1.49826 | yes | 0 | 700 | 지붕층 | 상위 레벨: 지붕층 | no | 구조체 면:외부 | 700 | yes | 보강 철근 피복 1 <25 mm> | 교좌장치 | 보강 철근 피복 1 <25 mm> | 10701.8 | 7.49129
2992267 | 옥탑층 | 700 | 5700 | 1.14 | 0.798 | 3.99 | 3.99 | 0.798 | yes | 0 | 700 | 지붕층 | 상위 레벨: 지붕층 | no | 구조체 면:외부 | 700 | yes | 보강 철근 피복 1 <25 mm> | 교좌장치 | 보강 철근 피복 1 <25 mm> | 5700 | 3.99
2992269 | 옥탑층 | 700 | 3399.99 | 0.679998 | 0.475999 | 2.37999 | 2.37999 | 0.475999 | yes | 0 | 700 | 지붕층 | 상위 레벨: 지붕층 | no | 구조체 면:외부 | 700 | yes | 보강 철근 피복 1 <25 mm> | 교좌장치 | 보강 철근 피복 1 <25 mm> | 3499.99 | 2.37999
2992271 | 옥탑층 | 700 | 4500 | 0.9 | 0.63 | 3.15 | 3.15 | 0.63 | yes | 0 | 700 | 지붕층 | 상위 레벨: 지붕층 | no | 구조체 면:외부 | 700 | yes | 보강 철근 피복 1 <25 mm> | 교좌장치 | 보강 철근 피복 1 <25 mm> | 4400 | 3.15
2992273 | 옥탑층 | 700 | 6500 | 1.3 | 0.91 | 4.55 | 4.55 | 0.91 | yes | 0 | 700 | 지붕층 | 상위 레벨: 지붕층 | no | 구조체 면:외부 | 700 | yes | 보강 철근 피복 1 <25 mm> | 교좌장치 | 보강 철근 피복 1 <25 mm> | 6700 | 4.55
3113000 | 지상 1층 | 3550 | 750 | 0.15 | 0.5325 | 2.6625 | 2.6625 | 0.5325 | yes | -550 | 3000 | 지상 1층 | 상위 레벨: 지상 1층 | no | 구조체 면:외부 | 3550 | yes | 보강 철근 피복 1 <25 mm> | 교좌장치 | 보강 철근 피복 1 <25 mm> | 925 | 2.6625
3152694 | 지하2층 | 1800 | 5601.85 | 1.12037 | 2.01666 | 10.0833 | 10.0833 | 2.01666 | yes | 0 | 0 | PIT | 상위 레벨: 지하2층 | no | 구조체 면:외부 | 1800 | yes | 보강 철근 피복 1 <25 mm> | 교좌장치 | 보강 철근 피복 1 <25 mm> | 5801.85 | 10.0833
3152696 | 지하2층 | 1800 | 3203.91 | 0.640782 | 1.15341 | 5.76704 | 5.76704 | 1.15341 | yes | 0 | 0 | PIT | 상위 레벨: 지하2층 | no | 구조체 면:외부 | 1800 | yes | 보강 철근 피복 1 <25 mm> | 교좌장치 | 보강 철근 피복 1 <25 mm> | 3203.91 | 5.76704
3152698 | 지하2층 | 1800 | 2800 | 0.56 | 1.008 | 5.04 | 5.04 | 1.008 | yes | 0 | 0 | PIT | 상위 레벨: 지하2층 | no | 구조체 면:외부 | 1800 | yes | 보강 철근 피복 1 <25 mm> | 교좌장치 | 보강 철근 피복 1 <25 mm> | 3000 | 5.04
3152700 | 지하2층 | 1800 | 2601.85 | 0.520369 | 0.936665 | 4.68332 | 4.68332 | 0.936665 | yes | 0 | 0 | PIT | 상위 레벨: 지하2층 | no | 구조체 면:외부 | 1800 | yes | 보강 철근 피복 1 <25 mm> | 교좌장치 | 보강 철근 피복 1 <25 mm> | 2801.85 | 4.68332
3152702 | 지하2층 | 1800 | 5601.85 | 1.12037 | 2.01666 | 10.0833 | 10.0833 | 2.01666 | yes | 0 | 0 | PIT | 상위 레벨: 지하2층 | no | 구조체 면:외부 | 1800 | yes | 보강 철근 피복 1 <25 mm> | 교좌장치 | 보강 철근 피복 1 <25 mm> | 5801.85 | 10.0833
3152704 | 지하2층 | 1800 | 2100 | 0.42 | 0.756 | 3.78 | 3.78 | 0.756 | yes | 0 | 0 | PIT | 상위 레벨: 지하2층 | no | 구조체 면:외부 | 1800 | yes | 보강 철근 피복 1 <25 mm> | 교좌장치 | 보강 철근 피복 1 <25 mm> | 2300 | 3.78
3157420 | 지상 1층 | 3000 | 1210 | 0.242 | 0.726 | 3.63 | 3.63 | 0.726 |  | 0 | -1800 | 지상 1층 | 상위 레벨: 지상 2층 | no | 벽 중심선 | 3000 | no |  | 비교좌장치 |  | 1210 | 3.63
3157421 | 지상 1층 | 3000 | 3945.7 | 0.78914 | 2.36742 | 11.8371 | 10.8771 | 2.17542 |  | 0 | -1800 | 지상 1층 | 상위 레벨: 지상 2층 | no | 벽 중심선 | 3000 | no |  | 비교좌장치 |  | 3945.7 | 10.8771
3157422 | 지상 1층 | 3000 | 1210 | 0.242 | 0.726 | 3.63 | 3.63 | 0.726 |  | 0 | -1800 | 지상 1층 | 상위 레벨: 지상 2층 | no | 벽 중심선 | 3000 | no |  | 비교좌장치 |  | 1210 | 3.63
3157423 | 지상 1층 | 3000 | 3945.7 | 0.78914 | 2.36742 | 11.8371 | 11.8371 | 2.36742 |  | 0 | -1800 | 지상 1층 | 상위 레벨: 지상 2층 | no | 벽 중심선 | 3000 | no |  | 비교좌장치 |  | 3945.7 | 11.8371
3157426 | 지하1층 | 5900 | 1210 | 0.242 | 1.4278 | 7.139 | 7.139 | 1.4278 |  | 0 | 0 | 지하1층 | 상위 레벨: GL | no | 벽 중심선 | 5950 | no |  | 비교좌장치 |  | 1210 | 7.139
3157427 | 지하1층 | 5900 | 3945.7 | 0.78914 | 4.65593 | 23.2796 | 23.2796 | 4.65593 |  | 0 | 0 | 지하1층 | 상위 레벨: GL | no | 벽 중심선 | 5950 | no |  | 비교좌장치 |  | 3945.7 | 23.2796
3157428 | 지하1층 | 5900 | 1210 | 0.242 | 1.4278 | 7.139 | 7.139 | 1.4278 |  | 0 | 0 | 지하1층 | 상위 레벨: GL | no | 벽 중심선 | 5950 | no |  | 비교좌장치 |  | 1210 | 7.139
3157429 | 지하1층 | 5900 | 3945.7 | 0.78914 | 4.65593 | 23.2796 | 23.2796 | 4.65593 |  | 0 | 0 | 지하1층 | 상위 레벨: GL | no | 벽 중심선 | 5950 | no |  | 비교좌장치 |  | 3945.7 | 23.2796
3173963 | 지하2층 | 3800 | 2700 | 0.54 | 2.052 | 10.26 | 10.26 | 2.052 | yes | 0 | 0 | 지하2층 | 상위 레벨: 지하1층 | no | 구조체 면:외부 | 4000 | yes |  | 교좌장치 | 보강 철근 피복 1 <25 mm> | 2900 | 10.26
3174298 | 지하2층 | 1640 | 2700 | 0.54 | 0.8856 | 4.428 | 4.428 | 0.8856 | yes | 0 | 0 | PIT | 상위 레벨: 지하2층 | no | 구조체 면:외부 | 1800 | yes | 보강 철근 피복 1 <25 mm> | 교좌장치 | 보강 철근 피복 1 <25 mm> | 2900 | 4.428
3174472 | 지하2층 | 1800 | 5500 | 1.1 | 1.98 | 9.9 | 9.9 | 1.98 | yes | 0 | 0 | PIT | 상위 레벨: 지하2층 | no | 구조체 면:외부 | 1800 | yes | 보강 철근 피복 1 <25 mm> | 교좌장치 | 보강 철근 피복 1 <25 mm> | 5700 | 9.9
3175447 | 지상 1층 | 5350 | 2200 | 0.44 | 2.354 | 11.77 | 11.77 | 2.354 | yes | -550 | 0 | 지상 1층 | 상위 레벨: 지상 2층 | no | 구조체 면:외부 | 5350 | yes | 보강 철근 피복 1 <25 mm> | 교좌장치 | 보강 철근 피복 1 <25 mm> | 2200 | 11.77
3175543 | 지상 1층 | 5350 | 2599.99 | 0.519998 | 2.78199 | 13.91 | 13.91 | 2.78199 | yes | -550 | 0 | 지상 1층 | 상위 레벨: 지상 2층 | no | 구조체 면:외부 | 5350 | yes | 보강 철근 피복 1 <25 mm> | 교좌장치 | 보강 철근 피복 1 <25 mm> | 2599.99 | 13.91
3176162 | 지상 2층 | 4500 | 2200 | 0.44 | 1.98 | 9.9 | 9.9 | 1.98 | yes | 0 | 0 | 지상 2층 | 상위 레벨: 지상 3층 | no | 구조체 면:외부 | 4500 | yes | 보강 철근 피복 1 <25 mm> | 교좌장치 | 보강 철근 피복 1 <25 mm> | 2200 | 9.9
3176164 | 지상 2층 | 4500 | 2499.99 | 0.499998 | 2.24999 | 11.25 | 11.25 | 2.24999 | yes | 0 | 0 | 지상 2층 | 상위 레벨: 지상 3층 | no | 구조체 면:외부 | 4500 | yes | 보강 철근 피복 1 <25 mm> | 교좌장치 | 보강 철근 피복 1 <25 mm> | 2599.99 | 11.25
3176168 | 지상 3층 | 4100 | 2200 | 0.44 | 1.804 | 9.02 | 9.02 | 1.804 | yes | 0 | 0 | 지상 3층 | 상위 레벨: 지상 4층 | no | 구조체 면:외부 | 4100 | yes | 보강 철근 피복 1 <25 mm> | 교좌장치 | 보강 철근 피복 1 <25 mm> | 2200 | 9.02
3176170 | 지상 3층 | 4100 | 2499.99 | 0.499998 | 2.04999 | 10.25 | 10.25 | 2.04999 | yes | 0 | 0 | 지상 3층 | 상위 레벨: 지상 4층 | no | 구조체 면:외부 | 4100 | yes | 보강 철근 피복 1 <25 mm> | 교좌장치 | 보강 철근 피복 1 <25 mm> | 2599.99 | 10.25
3176180 | 지상 5층 | 4100 | 2200 | 0.44 | 1.804 | 9.02 | 9.02 | 1.804 | yes | 0 | 0 | 지상 5층 | 상위 레벨: 지상 6층 | no | 구조체 면:외부 | 4100 | yes | 보강 철근 피복 1 <25 mm> | 교좌장치 | 보강 철근 피복 1 <25 mm> | 2200 | 9.02
3176182 | 지상 5층 | 4100 | 2499.99 | 0.499998 | 2.04999 | 10.25 | 10.25 | 2.04999 | yes | 0 | 0 | 지상 5층 | 상위 레벨: 지상 6층 | no | 구조체 면:외부 | 4100 | yes | 보강 철근 피복 1 <25 mm> | 교좌장치 | 보강 철근 피복 1 <25 mm> | 2599.99 | 10.25
3176186 | 지상 6층 | 4100 | 2200 | 0.44 | 1.804 | 9.02 | 9.02 | 1.804 | yes | 0 | 0 | 지상 6층 | 상위 레벨: 지상 7층 | no | 구조체 면:외부 | 4100 | yes | 보강 철근 피복 1 <25 mm> | 교좌장치 | 보강 철근 피복 1 <25 mm> | 2200 | 9.02
3176188 | 지상 6층 | 4100 | 2499.99 | 0.499998 | 2.04999 | 10.25 | 10.25 | 2.04999 | yes | 0 | 0 | 지상 6층 | 상위 레벨: 지상 7층 | no | 구조체 면:외부 | 4100 | yes | 보강 철근 피복 1 <25 mm> | 교좌장치 | 보강 철근 피복 1 <25 mm> | 2599.99 | 10.25
3176192 | 지상 7층 | 4100 | 2200 | 0.44 | 1.804 | 9.02 | 9.02 | 1.804 | yes | 0 | 0 | 지상 7층 | 상위 레벨: 지상 8층 | no | 구조체 면:외부 | 4100 | yes | 보강 철근 피복 1 <25 mm> | 교좌장치 | 보강 철근 피복 1 <25 mm> | 2200 | 9.02
3176194 | 지상 7층 | 4100 | 2499.99 | 0.499998 | 2.04999 | 10.25 | 10.25 | 2.04999 | yes | 0 | 0 | 지상 7층 | 상위 레벨: 지상 8층 | no | 구조체 면:외부 | 4100 | yes | 보강 철근 피복 1 <25 mm> | 교좌장치 | 보강 철근 피복 1 <25 mm> | 2599.99 | 10.25
3176198 | 지상 8층 | 4100 | 2200 | 0.44 | 1.804 | 9.02 | 9.02 | 1.804 | yes | 0 | 0 | 지상 8층 | 상위 레벨: 지상 9층 | no | 구조체 면:외부 | 4100 | yes | 보강 철근 피복 1 <25 mm> | 교좌장치 | 보강 철근 피복 1 <25 mm> | 2200 | 9.02
3176200 | 지상 8층 | 4100 | 2499.99 | 0.499998 | 2.04999 | 10.25 | 10.25 | 2.04999 | yes | 0 | 0 | 지상 8층 | 상위 레벨: 지상 9층 | no | 구조체 면:외부 | 4100 | yes | 보강 철근 피복 1 <25 mm> | 교좌장치 | 보강 철근 피복 1 <25 mm> | 2599.99 | 10.25
3176204 | 지상 9층 | 4500 | 2200 | 0.44 | 1.98 | 9.9 | 9.9 | 1.98 | yes | 0 | 0 | 지상 9층 | 상위 레벨: 지상 10층 | no | 구조체 면:외부 | 4500 | yes | 보강 철근 피복 1 <25 mm> | 교좌장치 | 보강 철근 피복 1 <25 mm> | 2200 | 9.9
3176206 | 지상 9층 | 4500 | 2499.99 | 0.499998 | 2.24999 | 11.25 | 11.25 | 2.24999 | yes | 0 | 0 | 지상 9층 | 상위 레벨: 지상 10층 | no | 구조체 면:외부 | 4500 | yes | 보강 철근 피복 1 <25 mm> | 교좌장치 | 보강 철근 피복 1 <25 mm> | 2599.99 | 11.25
3176999 | 지상 4층 | 4100 | 2200 | 0.44 | 1.804 | 9.02 | 9.02 | 1.804 | yes | 0 | 0 | 지상 4층 | 상위 레벨: 지상 5층 | no | 구조체 면:외부 | 4100 | yes | 보강 철근 피복 1 <25 mm> | 교좌장치 | 보강 철근 피복 1 <25 mm> | 2200 | 9.02
3177001 | 지상 4층 | 4100 | 2499.99 | 0.499998 | 2.04999 | 10.25 | 10.25 | 2.04999 | yes | 0 | 0 | 지상 4층 | 상위 레벨: 지상 5층 | no | 구조체 면:외부 | 4100 | yes | 보강 철근 피복 1 <25 mm> | 교좌장치 | 보강 철근 피복 1 <25 mm> | 2599.99 | 10.25
3184767 | 지상 1층 | 900 | 7600 | 1.52 | 1.368 | 6.84 | 6.84 | 1.368 | yes | -550 | 350 | 지상 1층 | 상위 레벨: 지상 1층 | no | 구조체 면:외부 | 900 | yes | 보강 철근 피복 1 <25 mm> | 교좌장치 | 보강 철근 피복 1 <25 mm> | 7800 | 6.84
3185229 | 지상 1층 | 1910 | 902.3 | 0.18046 | 0.312679 | 1.56339 | 1.56339 | 0.312679 | yes | -1560 | 350 | 지상 1층 | 상위 레벨: 지상 1층 | no | 구조체 면:외부 | 1910 | yes | 보강 철근 피복 1 <25 mm> | 교좌장치 | 보강 철근 피복 1 <25 mm> | 802.3 | 1.56339
3186342 | 지상 1층 | 1000 | 6500 | 1.3 | 1.3 | 6.5 | 6.5 | 1.3 |  | 500 | 1500 | 지상 1층 | 상위 레벨: 지상 1층 | no | 벽 중심선 | 1000 | no |  | 비교좌장치 |  | 6600 | 6.5
3186954 | 지상 1층 | 900 | 1570.04 | 0.314009 | 0.282608 | 1.41304 | 1.41304 | 0.282608 |  | -550 | 350 | 지상 1층 | 상위 레벨: 지상 1층 | no | 벽 중심선 | 900 | no |  | 비교좌장치 |  | 1745.04 | 1.41304
3186996 | 지상 1층 | 900 | 700 | 0.14 | 0.126 | 0.63 | 0.63 | 0.126 |  | -550 | 350 | 지상 1층 | 상위 레벨: 지상 1층 | no | 벽 중심선 | 900 | no |  | 비교좌장치 |  | 500 | 0.63
3187032 | 지상 1층 | 900 | 2200 | 0.44 | 0.396 | 1.98 | 1.98 | 0.396 |  | -550 | 350 | 지상 1층 | 상위 레벨: 지상 1층 | no | 벽 중심선 | 900 | no |  | 비교좌장치 |  | 2200 | 1.98
3187143 | 지상 1층 | 900 | 1159.96 | 0.231991 | 0.208792 | 1.04396 | 1.04396 | 0.208792 |  | -550 | 350 | 지상 1층 | 상위 레벨: 지상 1층 | no | 벽 중심선 | 900 | no |  | 비교좌장치 |  | 1259.96 | 1.04396
3187234 | 지상 1층 | 900 | 2435.33 | 0.487066 | 0.43836 | 2.1918 | 2.1918 | 0.43836 |  | -550 | 350 | 지상 1층 | 상위 레벨: 지상 1층 | no | 벽 중심선 | 900 | no |  | 비교좌장치 |  | 2510.33 | 2.1918
3187348 | 지상 1층 | 900 | 500 | 0.1 | 0.09 | 0.45 | 0.45 | 0.09 |  | -550 | 350 | 지상 1층 | 상위 레벨: 지상 1층 | no | 벽 중심선 | 900 | no |  | 비교좌장치 |  | 500 | 0.45
3187472 | 지상 1층 | 900 | 1413.72 | 0.282739 | 0.036 | 0.18 | 1.41372 | 0.254467 |  | -550 | 350 | 지상 1층 | 상위 레벨: 지상 1층 | no | 벽 중심선 | 900 | no |  | 비교좌장치 |  | 1413.72 | 1.41372 | 그래픽 - 중심 마크 보기: no
3187621 | 지상 1층 | 900 | 2400.04 | 0.480009 | 0.432008 | 2.16004 | 2.16004 | 0.432008 |  | -550 | 350 | 지상 1층 | 상위 레벨: 지상 1층 | no | 벽 중심선 | 900 | no |  | 비교좌장치 |  | 2575.04 | 2.16004
3187700 | 지상 1층 | 900 | 2000 | 0.4 | 0.36 | 1.8 | 1.8 | 0.36 |  | -550 | 350 | 지상 1층 | 상위 레벨: 지상 1층 | no | 벽 중심선 | 900 | no |  | 비교좌장치 |  | 2200 | 1.8
3187751 | 지상 1층 | 870 | 2799.97 | 0.559993 | 0.487194 | 2.43597 | 2.43597 | 0.487194 |  | -520 | 350 | 지상 1층 | 상위 레벨: 지상 1층 | no | 벽 중심선 | 870 | no |  | 비교좌장치 |  | 2899.97 | 2.43597
3187932 | 지상 1층 | 900 | 700 | 0.14 | 0.126 | 0.63 | 0.63 | 0.126 |  | -550 | 350 | 지상 1층 | 상위 레벨: 지상 1층 | no | 벽 중심선 | 900 | no |  | 비교좌장치 |  | 500 | 0.63
3187977 | 지상 1층 | 900 | 700 | 0.14 | 0.126 | 0.63 | 0.63 | 0.126 |  | -550 | 350 | 지상 1층 | 상위 레벨: 지상 1층 | no | 벽 중심선 | 900 | no |  | 비교좌장치 |  | 500 | 0.63
3189196 | 지상 1층 | 550 | 2374.71 | 0.474942 | 0.261218 | 1.30609 | 1.30609 | 0.261218 | no | 200 | 750 | 지상 1층 | 상위 레벨: 지상 1층 | no | 벽 중심선 | 550 | no |  | 비교좌장치 |  | 2474.71 | 1.30609
5256435 | 지상 3층 | 3950 | 7899.99 | 1.58 | 5.84955 | 29.2478 | 29.2478 | 5.84955 |  | 0 | 0 | 지상 3층 | 상위 레벨: 지상 4층 | no | 벽 중심선 | 4100 | no |  | 비교좌장치 |  | 7899.99 | 29.2478
5256523 | 지상 3층 | 4100 | 4850 | 0.97 | 3.977 | 19.885 | 19.885 | 3.977 |  | 0 | 0 | 지상 3층 | 상위 레벨: 지상 4층 | no | 벽 중심선 | 4100 | no |  | 비교좌장치 |  | 5050 | 19.885
5382185 | 지상 1층 | 400 | 9100.01 | 1.82 | 0.728001 | 3.64 | 3.64 | 0.728001 | yes | -1500 | -1100 | 지상 1층 | 상위 레벨: 지상 1층 | no | 구조체 면:외부 | 400 | yes | 보강 철근 피복 1 <25 mm> | 교좌장치 | 보강 철근 피복 1 <25 mm> | 9100.01 | 3.64
5903096 | 지상 2층 | 4350 | 7899.99 | 1.58 | 6.87299 | 34.365 | 32.37 | 6.47399 |  | 0 | 0 | 지상 2층 | 상위 레벨: 지상 3층 | no | 벽 중심선 | 4500 | no |  | 비교좌장치 |  | 7899.99 | 32.37
5903097 | 지상 2층 | 4350 | 4850 | 0.97 | 4.2195 | 21.0975 | 21.0975 | 4.2195 |  | 0 | 0 | 지상 2층 | 상위 레벨: 지상 3층 | no | 벽 중심선 | 4500 | no |  | 비교좌장치 |  | 5050 | 21.0975
5903103 | 지상 9층 | 4350 | 8099.99 | 1.62 | 7.04699 | 35.235 | 33.345 | 6.66899 |  | 0 | 0 | 지상 9층 | 상위 레벨: 지상 10층 | no | 벽 중심선 | 4500 | no |  | 비교좌장치 |  | 8074.99 | 33.345
5903104 | 지상 9층 | 4270 | 4850 | 0.97 | 4.1419 | 20.7095 | 20.7095 | 4.1419 |  | 0 | 0 | 지상 9층 | 상위 레벨: 지상 10층 | no | 벽 중심선 | 4500 | no |  | 비교좌장치 |  | 5050 | 20.7095
5915467 | 지상 1층 | 5350 | 1500 | 0.3 | 1.0394 | 5.19702 | 5.19702 | 1.0394 | yes | -550 | 0 | 지상 1층 | 상위 레벨: 지상 2층 | no | 구조체 면:외부 | 5350 | yes | 보강 철근 피복 1 <25 mm> | 교좌장치 | 보강 철근 피복 1 <25 mm> | 1700 | 5.19702
5998070 | 지하2층 | 4000 | 5601.85 | 1.12037 | 4.48148 | 22.4074 | 16.7974 | 3.35948 | yes | 0 | 0 | 지하2층 | 상위 레벨: 지하1층 | no | 구조체 면:외부 | 4000 | yes | 보강 철근 피복 1 <25 mm> | 교좌장치 | 보강 철근 피복 1 <25 mm> | 5701.85 | 16.7974
5999548 | 지상 6층 | 3950 | 7700 | 1.54 | 6.083 | 30.415 | 28.015 | 5.603 | yes | 0 | 0 | 지상 6층 | 상위 레벨: 지상 7층 | no | 구조체 면:외부 | 4100 | yes | 보강 철근 피복 1 <25 mm> | 교좌장치 | 보강 철근 피복 1 <25 mm> | 7600 | 28.015
5999768 | 지상 7층 | 4100 | 7700 | 1.54 | 6.314 | 31.57 | 29.17 | 5.834 | yes | 0 | 0 | 지상 7층 | 상위 레벨: 지상 8층 | no | 구조체 면:외부 | 4100 | yes | 보강 철근 피복 1 <25 mm> | 교좌장치 | 보강 철근 피복 1 <25 mm> | 7600 | 29.17
5999969 | 지상 8층 | 3950 | 7700 | 1.54 | 6.083 | 30.415 | 28.015 | 5.603 | yes | 0 | 0 | 지상 8층 | 상위 레벨: 지상 9층 | no | 구조체 면:외부 | 4100 | yes | 보강 철근 피복 1 <25 mm> | 교좌장치 | 보강 철근 피복 1 <25 mm> | 7600 | 28.015

# IfcWallStandardCase: 기본 벽:WA111-철근콘크리트구조 벽 200mm_CW2 (5)
In: 지하1층
Type - PredefinedType: STANDARD; Material: KBIMS-콘크리트 200 mm
Type - ID 데이터 - 단가: 0; 유형 마크: CW2; 유형 이름: WA111-철근콘크리트구조 벽 200mm_CW2
Type - 그래픽 - 거친 축척 채우기 색상: 0
Type - 기타 - 내화구조여부: yes; 주요구조부여부: yes; 카테고리: 벽; KBIMS-부위코드: E275; 조달청표준공사코드: AD; 패밀리 이름: 기본 벽
Type - 시공 - 기능: 외부; 끝단부 마무리: 없음; 인서트 부위 마무리: 마무리하지 않음; 폭: 200 mm
Type - 재료 및 마감재 - 구조 재료: KBIMS-콘크리트
Type - 해석 특성 - 거칠기: 1; 열 저항(R): 0.191205; 열 전달 계수(U): 5.23 kg/K/s3; 열 질량: 302.22; 흡수율: 9290.3
Type - Pset_WallCommon - IsExternal: yes; ThermalTransmittance: 5.23 kg/K/s3
BaseQuantities - Width: 200 mm
ID 데이터 - 연관 있음: yes
공정 - 생성 공정: 새 구성
구속조건 - 베이스 간격띄우기: 0 mm; 매스와 관련됨: no; 룸 경계: yes; 베이스 확장 거리: 0 mm; 벽 베이스가 부착됩니다.: no; 상단 확장 거리: 0 mm; 상단이 부착됩니다.: no; 위치선: 구조체 면:외부; 베이스 구속조건: 지하1층; 상단 구속조건: 상위 레벨: 지상 1층
구조 - 구조: yes; 보강 철근 피복 - 다른 면: 보강 철근 피복 1 <25 mm>; 구조적 용도: 교좌장치; 보강 철근 피복 - 내부 면: 보강 철근 피복 1 <25 mm>; 보강 철근 피복 - 외부 면: 보강 철근 피복 1 <25 mm>
기타 - 패밀리: 기본 벽; 유형: WA111-철근콘크리트구조 벽 200mm_CW2; 유형 ID: 7626131; 패밀리 및 유형: 기본 벽: WA111-철근콘크리트구조 벽 200mm_CW2
단면형상 정의 - 단면형상: 수직
Pset_QuantityTakeOff - Reference: WA111-철근콘크리트구조 벽 200mm_CW2; sets with these values: 2
Pset_WallCommon - LoadBearing: yes; ExtendToStructure: no; Reference: WA111-철근콘크리트구조 벽 200mm_CW2
Name (기본 벽:WA111-철근콘크리트구조 벽 200mm_CW2:...) | Height (mm) = 미연결 높이 (mm) | Length (mm) | GrossFootprintArea (m2) | GrossVolume (m3) | GrossSideArea (m2) | NetSideArea (m2) = 면적 (m2) | NetVolume (m3) = 체적 (m3) | 상단 간격띄우기 (mm) | 길이 (mm)
2816471 | 5500 | 5501.85 | 1.10037 | 6.05203 | 30.2602 | 27.9502 | 5.59003 | -600 | 5701.85
2816473 | 6100 | 3203.91 | 0.640782 | 3.90877 | 19.5438 | 19.5438 | 3.90877 | 0 | 3203.91
2816475 | 6100 | 2800 | 0.56 | 3.416 | 17.08 | 17.08 | 3.416 | 0 | 3000
2816477 | 6100 | 2501.85 | 0.500369 | 3.05225 | 15.2613 | 15.2613 | 3.05225 | 0 | 2701.85
2816479 | 6100 | 5501.85 | 1.10037 | 6.71225 | 33.5613 | 32.6013 | 6.52025 | 0 | 5701.85

# IfcWallStandardCase: 기본 벽:WA111-철근콘크리트구조 벽 200mm_W1 (33)
Type - PredefinedType: STANDARD; Material: KBIMS-콘크리트 200 mm
Type - ID 데이터 - 단가: 0; 유형 마크: W1; 유형 이름: WA111-철근콘크리트구조 벽 200mm_W1
Type - 그래픽 - 거친 축척 채우기 색상: 0
Type - 기타 - 내화구조여부: yes; 주요구조부여부: yes; 카테고리: 벽; KBIMS-부위코드: E275; 조달청표준공사코드: AD; 패밀리 이름: 기본 벽
Type - 시공 - 기능: 외부; 끝단부 마무리: 없음; 인서트 부위 마무리: 마무리하지 않음; 폭: 200 mm
Type - 재료 및 마감재 - 구조 재료: KBIMS-콘크리트
Type - 해석 특성 - 거칠기: 1; 열 저항(R): 0.191205; 열 전달 계수(U): 5.23 kg/K/s3; 열 질량: 302.22; 흡수율: 9290.3
Type - Pset_WallCommon - IsExternal: yes; ThermalTransmittance: 5.23 kg/K/s3
BaseQuantities - Width: 200 mm
공정 - 생성 공정: 새 구성
구속조건 - 매스와 관련됨: no; 베이스 확장 거리: 0 mm; 벽 베이스가 부착됩니다.: no; 상단 확장 거리: 0 mm; 상단이 부착됩니다.: no
기타 - 패밀리: 기본 벽; 유형: WA111-철근콘크리트구조 벽 200mm_W1; 유형 ID: 7626970; 패밀리 및 유형: 기본 벽: WA111-철근콘크리트구조 벽 200mm_W1
단면형상 정의 - 단면형상: 수직
Pset_QuantityTakeOff - Reference: WA111-철근콘크리트구조 벽 200mm_W1; sets with these values: 2
Pset_WallCommon - ExtendToStructure: no; Reference: WA111-철근콘크리트구조 벽 200mm_W1
Name (기본 벽:WA111-철근콘크리트구조 벽 200mm_W1:...) | In | Height (mm) | Length (mm) | GrossFootprintArea (m2) | GrossVolume (m3) | GrossSideArea (m2) | NetSideArea (m2) = 면적 (m2) | NetVolume (m3) = 체적 (m3) | 연관 있음 | 베이스 간격띄우기 (mm) | 룸 경계 | 상단 간격띄우기 (mm) | 베이스 구속조건 | 상단 구속조건 | 위치선 | 미연결 높이 (mm) | 구조 = LoadBearing | 보강 철근 피복 - 다른 면 = 보강 철근 피복 - 내부 면 = 보강 철근 피복 - 외부 면 | 구조적 용도 | 길이 (mm)
2814928 | 지하2층 | 4000 | 5258.91 | 1.02115 | 4.20713 | 21.0357 | 21.0357 | 4.0846 | yes | 0 | yes | 0 | 지하2층 | 상위 레벨: 지하1층 | 구조체 면:외부 | 4000 | yes | 보강 철근 피복 1 <25 mm> | 교좌장치 | 5965.68
2815051 | 지하2층 | 5600 | 5291.05 | 1.05077 | 0.756 | 3.78 | 25.8499 | 5.1283 | yes | -1800 | yes | 0 | 지하2층 | 상위 레벨: 지하1층 | 구조체 면:외부 | 5800 | yes | 보강 철근 피복 1 <25 mm> | 교좌장치 | 5823.97
2815303 | 지하2층 | 5800 | 5049.99 | 1.01 | 5.66999 | 28.35 | 24.57 | 4.91399 | yes | -1800 | no | 0 | 지하2층 | 상위 레벨: 지하1층 | 구조체 면:외부 | 5800 | yes | 보강 철근 피복 1 <25 mm> | 교좌장치 | 4999.99
2816489 | 지하1층 | 5950 | 5358.95 | 1.04116 | 6.37715 | 31.8857 | 31.8857 | 6.19489 | yes | 0 | yes | -150 | 지하1층 | 상위 레벨: 지상 1층 | 구조체 면:외부 | 5950 | yes | 보강 철근 피복 1 <25 mm> | 교좌장치 | 6015.72
2818398 | 지상 1층 | 4650 | 15198.2 | 3.03963 | 14.1343 | 70.6714 | 62.8474 | 12.5695 | yes | 0 | yes | 0 | 지상 1층 | 상위 레벨: 지상 2층 | 구조체 면:외부 | 4800 | yes | 보강 철근 피복 1 <25 mm> | 교좌장치 | 15298.2
2819460 | 지상 1층 | 6150 | 9101.01 | 1.8202 | 0.72 | 3.6 | 52.3712 | 10.4742 | yes | -1500 | yes | 0 | 지상 1층 | 상위 레벨: 지상 2층 | 구조체 면:외부 | 6300 | yes | 보강 철근 피복 1 <25 mm> | 교좌장치 | 9092.01
2819622 | 지상 1층 | 5150 | 10375 | 2.075 | 5.63316 | 28.1658 | 28.1658 | 5.63316 | yes | -500 | yes | 0 | 지상 1층 | 상위 레벨: 지상 2층 | 구조체 면:외부 | 5300 | yes | 보강 철근 피복 1 <25 mm> | 교좌장치 | 10537.5
2820046 | 지상 2층 | 4500 | 15200 | 3.04 | 13.5975 | 67.9875 | 60.6435 | 12.1287 | yes | 0 | yes | 0 | 지상 2층 | 상위 레벨: 지상 3층 | 구조체 면:외부 | 4500 | yes | 보강 철근 피복 1 <25 mm> | 교좌장치 | 15300
2820463 | 지상 3층 | 4100 | 15200 | 3.04 | 11.7006 | 58.5031 | 54.9031 | 10.9806 | yes | 0 | yes | 0 | 지상 3층 | 상위 레벨: 지상 4층 | 구조체 면:외부 | 4100 | yes | 보강 철근 피복 1 <25 mm> | 교좌장치 | 15300
2820483 | 지상 3층 | 3950 | 9100.01 | 1.82 | 7.18901 | 35.945 | 12.3886 | 2.47772 | yes | 0 | yes | 0 | 지상 3층 | 상위 레벨: 지상 4층 | 구조체 면:외부 | 4100 | yes | 보강 철근 피복 1 <25 mm> | 교좌장치 | 9082.01
2820713 | 지상 4층 | 3950 | 15200 | 3.04 | 12.008 | 60.04 | 56.44 | 11.288 | yes | 0 | yes | 0 | 지상 4층 | 상위 레벨: 지상 5층 | 구조체 면:외부 | 4100 | yes | 보강 철근 피복 1 <25 mm> | 교좌장치 | 15300
2820733 | 지상 4층 | 3950 | 9101.01 | 1.8202 | 0.72 | 3.6 | 32.349 | 6.4698 | yes | 0 | yes | 0 | 지상 4층 | 상위 레벨: 지상 5층 | 구조체 면:외부 | 4100 | yes | 보강 철근 피복 1 <25 mm> | 교좌장치 | 9101.01
2821215 | 지상 5층 | 3950 | 15200 | 3.04 | 12.008 | 60.04 | 56.44 | 11.288 | yes | 0 | yes | 0 | 지상 5층 | 상위 레벨: 지상 6층 | 구조체 면:외부 | 4100 | yes | 보강 철근 피복 1 <25 mm> | 교좌장치 | 15300
2821235 | 지상 5층 | 3950 | 9300.01 | 1.86 | 7.34701 | 36.735 | 33.135 | 6.62701 | yes | 0 | yes | 0 | 지상 5층 | 상위 레벨: 지상 6층 | 구조체 면:외부 | 4100 | yes | 보강 철근 피복 1 <25 mm> | 교좌장치 | 9300.01
2821475 | 지상 6층 | 3950 | 15200 | 3.04 | 0.72 | 3.6 | 56.44 | 11.288 | yes | 0 | yes | 0 | 지상 6층 | 상위 레벨: 지상 7층 | 구조체 면:외부 | 4100 | yes | 보강 철근 피복 1 <25 mm> | 교좌장치 | 15300
2821495 | 지상 6층 | 3950 | 9300.01 | 1.86 | 7.34701 | 36.735 | 33.135 | 6.62701 | yes | 0 | yes | 0 | 지상 6층 | 상위 레벨: 지상 7층 | 구조체 면:외부 | 4100 | yes | 보강 철근 피복 1 <25 mm> | 교좌장치 | 9300.01
2821671 | 지상 7층 | 3950 | 15200 | 3.04 | 12.008 | 60.04 | 56.44 | 11.288 | yes | 0 | yes | 0 | 지상 7층 | 상위 레벨: 지상 8층 | 구조체 면:외부 | 4100 | yes | 보강 철근 피복 1 <25 mm> | 교좌장치 | 15300
2821691 | 지상 7층 | 3950 | 9300.01 | 1.86 | 7.34701 | 36.735 | 33.135 | 6.62701 | yes | 0 | yes | 0 | 지상 7층 | 상위 레벨: 지상 8층 | 구조체 면:외부 | 4100 | yes | 보강 철근 피복 1 <25 mm> | 교좌장치 | 9300.01
2822017 | 지상 8층 | 3950 | 15300 | 3.06 | 12.087 | 60.435 | 56.835 | 11.367 | yes | 0 | yes | 0 | 지상 8층 | 상위 레벨: 지상 9층 | 구조체 면:외부 | 4100 | yes | 보강 철근 피복 1 <25 mm> | 교좌장치 | 15400
2822037 | 지상 8층 | 3950 | 9300.01 | 1.86 | 7.34701 | 36.735 | 33.135 | 6.62701 | yes | 0 | yes | 0 | 지상 8층 | 상위 레벨: 지상 9층 | 구조체 면:외부 | 4100 | yes | 보강 철근 피복 1 <25 mm> | 교좌장치 | 9300.01
2822223 | 지상 9층 | 4500 | 15300 | 3.06 | 13.3935 | 66.9675 | 63.3675 | 12.6735 | yes | 0 | yes | 0 | 지상 9층 | 상위 레벨: 지상 10층 | 구조체 면:외부 | 4500 | yes | 보강 철근 피복 1 <25 mm> | 교좌장치 | 15400
2822243 | 지상 9층 | 4350 | 9280.01 | 1.856 | 8.07361 | 40.368 | 36.768 | 7.35361 | yes | 0 | yes | 0 | 지상 9층 | 상위 레벨: 지상 10층 | 구조체 면:외부 | 4500 | yes | 보강 철근 피복 1 <25 mm> | 교좌장치 | 9280.01
2989353 | 옥탑층 | 1300 | 13300 | 2.66 | 3.458 | 17.29 | 17.29 | 3.458 | yes | 0 | yes | -2700 | 옥탑층 | 상위 레벨: 지붕층 | 구조체 면:외부 | 1300 | yes | 보강 철근 피복 1 <25 mm> | 교좌장치 | 13275
3157364 | 지하2층 | 4000 | 1210 | 0.242 | 0.968 | 4.84 | 4.84 | 0.968 |  | 0 | yes | 0 | 지하2층 | 상위 레벨: 지하1층 | 벽 중심선 | 4000 | no |  | 비교좌장치 | 1210
3157365 | 지하2층 | 4000 | 3945.7 | 0.78914 | 3.15656 | 15.7828 | 15.7828 | 3.15656 |  | 0 | yes | 0 | 지하2층 | 상위 레벨: 지하1층 | 벽 중심선 | 4000 | no |  | 비교좌장치 | 3945.7
3157366 | 지하2층 | 4000 | 1210 | 0.242 | 0.968 | 4.84 | 4.84 | 0.968 |  | 0 | yes | 0 | 지하2층 | 상위 레벨: 지하1층 | 벽 중심선 | 4000 | no |  | 비교좌장치 | 1210
3157367 | 지하2층 | 4000 | 3945.7 | 0.78914 | 3.15656 | 15.7828 | 15.7828 | 3.15656 |  | 0 | yes | 0 | 지하2층 | 상위 레벨: 지하1층 | 벽 중심선 | 4000 | no |  | 비교좌장치 | 3945.7
3188625 | 지상 1층 | 1000 | 2900 | 0.58 | 0.58 | 2.9 | 2.9 | 0.58 | no | 500 | yes | 1500 | 지상 1층 | 상위 레벨: 지상 1층 | 벽 중심선 | 1000 | no |  | 비교좌장치 | 3000
5998771 | 지상 2층 | 4350 | 7700 | 1.54 | 6.699 | 33.495 | 31.095 | 6.219 | yes | 0 | yes | 0 | 지상 2층 | 상위 레벨: 지상 3층 | 구조체 면:외부 | 4500 | yes | 보강 철근 피복 1 <25 mm> | 교좌장치 | 7600
5998918 | 지상 3층 | 3950 | 7700 | 1.54 | 0.48 | 2.4 | 28.015 | 5.603 | yes | 0 | yes | 0 | 지상 3층 | 상위 레벨: 지상 4층 | 구조체 면:외부 | 4100 | yes | 보강 철근 피복 1 <25 mm> | 교좌장치 | 7600
5999125 | 지상 4층 | 3950 | 7700 | 1.54 | 6.083 | 30.415 | 28.015 | 5.603 | yes | 0 | yes | 0 | 지상 4층 | 상위 레벨: 지상 5층 | 구조체 면:외부 | 4100 | yes | 보강 철근 피복 1 <25 mm> | 교좌장치 | 7600
5999356 | 지상 5층 | 3950 | 7700 | 1.54 | 6.083 | 30.415 | 28.015 | 5.603 | yes | 0 | yes | 0 | 지상 5층 | 상위 레벨: 지상 6층 | 구조체 면:외부 | 4100 | yes | 보강 철근 피복 1 <25 mm> | 교좌장치 | 7600
6000137 | 지상 9층 | 4500 | 7700 | 1.54 | 6.8505 | 34.2525 | 31.8525 | 6.3705 | yes | 0 | yes | 0 | 지상 9층 | 상위 레벨: 지상 10층 | 구조체 면:외부 | 4500 | yes | 보강 철근 피복 1 <25 mm> | 교좌장치 | 7600

# IfcWallStandardCase: 기본 벽:WA111-철근콘크리트구조 벽 200mm_W2, 기본 벽:WA111-철근콘크리트구조 벽 200mm_W2:2816483
In: 지하1층
Type - PredefinedType: STANDARD; Material: KBIMS-콘크리트 200 mm
Type - ID 데이터 - 단가: 0; 유형 마크: W2; 유형 이름: WA111-철근콘크리트구조 벽 200mm_W2
Type - 그래픽 - 거친 축척 채우기 색상: 0
Type - 기타 - 내화구조여부: yes; 주요구조부여부: yes; 카테고리: 벽; KBIMS-부위코드: E275; 조달청표준공사코드: AD; 패밀리 이름: 기본 벽
Type - 시공 - 기능: 외부; 끝단부 마무리: 없음; 인서트 부위 마무리: 마무리하지 않음; 폭: 200 mm
Type - 재료 및 마감재 - 구조 재료: KBIMS-콘크리트
Type - 해석 특성 - 거칠기: 1; 열 저항(R): 0.191205; 열 전달 계수(U): 5.23 kg/K/s3; 열 질량: 302.22; 흡수율: 9290.3
Type - Pset_WallCommon - IsExternal: yes; ThermalTransmittance: 5.23 kg/K/s3
BaseQuantities - Height: 5950 mm; Length: 4797.24 mm; Width: 200 mm; GrossFootprintArea: 0.95957 m2; GrossVolume: 5.70872 m3; GrossSideArea: 28.5436 m2; NetSideArea: 24.7636 m2; NetVolume: 4.95344 m3
ID 데이터 - 연관 있음: yes
공정 - 생성 공정: 새 구성
구속조건 - 베이스 간격띄우기: 0 mm; 매스와 관련됨: no; 룸 경계: yes; 베이스 확장 거리: 0 mm; 벽 베이스가 부착됩니다.: no; 상단 확장 거리: 0 mm; 상단이 부착됩니다.: no; 위치선: 구조체 면:외부; 베이스 구속조건: 지하1층; 상단 구속조건: 상위 레벨: 지상 1층; 미연결 높이: 5950 mm; 상단 간격띄우기: -150 mm
구조 - 구조: yes; 보강 철근 피복 - 다른 면: 보강 철근 피복 1 <25 mm>; 구조적 용도: 교좌장치; 보강 철근 피복 - 내부 면: 보강 철근 피복 1 <25 mm>; 보강 철근 피복 - 외부 면: 보강 철근 피복 1 <25 mm>
기타 - 패밀리: 기본 벽; 유형: WA111-철근콘크리트구조 벽 200mm_W2; 유형 ID: 7625935; 패밀리 및 유형: 기본 벽: WA111-철근콘크리트구조 벽 200mm_W2
단면형상 정의 - 단면형상: 수직
치수 - 길이: 5198.15 mm; 면적: 24.7636 m2; 체적: 4.95344 m3
Pset_QuantityTakeOff - Reference: WA111-철근콘크리트구조 벽 200mm_W2; sets with these values: 2
Pset_WallCommon - LoadBearing: yes; ExtendToStructure: no; Reference: WA111-철근콘크리트구조 벽 200mm_W2

# IfcWallStandardCase: 기본 벽:WA111-철근콘크리트구조 벽 300mm_RaW1 (8)
Type - PredefinedType: STANDARD; Material: KBIMS-콘크리트 600 mm
Type - ID 데이터 - 단가: 0; 유형 마크: RaW1; 유형 이름: WA111-철근콘크리트구조 벽 300mm_RaW1
Type - 그래픽 - 거친 축척 채우기 색상: 0
Type - 기타 - 내화구조여부: yes; 주요구조부여부: yes; 카테고리: 벽; KBIMS-부위코드: E275; 조달청표준공사코드: AD; 패밀리 이름: 기본 벽
Type - 시공 - 기능: 외부; 끝단부 마무리: 없음; 인서트 부위 마무리: 마무리하지 않음; 폭: 600 mm
Type - 재료 및 마감재 - 구조 재료: KBIMS-콘크리트
Type - 해석 특성 - 거칠기: 1; 열 저항(R): 0.573614; 열 전달 계수(U): 1.74333 kg/K/s3; 열 질량: 906.66; 흡수율: 9290.3
Type - Pset_WallCommon - IsExternal: yes; ThermalTransmittance: 1.74333 kg/K/s3
BaseQuantities - Width: 600 mm
ID 데이터 - 연관 있음: yes
공정 - 생성 공정: 새 구성
구속조건 - 베이스 간격띄우기: 0 mm; 매스와 관련됨: no; 룸 경계: yes; 베이스 확장 거리: 0 mm; 벽 베이스가 부착됩니다.: no; 상단 확장 거리: 0 mm; 상단이 부착됩니다.: no; 위치선: 구조체 면:외부
구조 - 구조: yes; 보강 철근 피복 - 다른 면: 보강 철근 피복 1 <25 mm>; 구조적 용도: 교좌장치; 보강 철근 피복 - 내부 면: 보강 철근 피복 1 <25 mm>; 보강 철근 피복 - 외부 면: 보강 철근 피복 1 <25 mm>
기타 - 패밀리: 기본 벽; 유형: WA111-철근콘크리트구조 벽 300mm_RaW1; 유형 ID: 7627184; 패밀리 및 유형: 기본 벽: WA111-철근콘크리트구조 벽 300mm_RaW1
단면형상 정의 - 단면형상: 수직
Pset_QuantityTakeOff - Reference: WA111-철근콘크리트구조 벽 300mm_RaW1; sets with these values: 2
Pset_WallCommon - LoadBearing: yes; ExtendToStructure: no; Reference: WA111-철근콘크리트구조 벽 300mm_RaW1
Name (기본 벽:WA111-철근콘크리트구조 벽 300mm_RaW1:...) | In | Height (mm) = 미연결 높이 (mm) | Length (mm) | GrossFootprintArea (m2) | GrossVolume (m3) | GrossSideArea (m2) | NetSideArea (m2) = 면적 (m2) | NetVolume (m3) = 체적 (m3) | 상단 간격띄우기 (mm) | 베이스 구속조건 | 상단 구속조건 | 길이 (mm) | 중심 마크 보기
2814746 | 지하2층 | 4000 | 5000 | 3 | 12 | 20 | 20 | 12 | 0 | 지하2층 | 상위 레벨: 지하1층 | 5100
2814759 | 지하2층 | 4000 | 9216.08 | 5.52641 | 1.44021 | 2.40036 | 38.7274 | 22.101 | 0 | 지하2층 | 상위 레벨: 지하1층 | 9110.62 | no
2815347 | 지하2층 | 4000 | 4826.65 | 2.82425 | 1.54498 | 2.57496 | 18.8505 | 11.297 | 0 | 지하2층 | 상위 레벨: 지하1층 | 4599.92 | no
2815361 | 지하2층 | 4000 | 13363.7 | 7.95925 | 1.44 | 2.4 | 54.55 | 31.8653 | 0 | 지하2층 | 상위 레벨: 지하1층 | 13363.7 | no
2816485 | 지하1층 | 5550 | 10200 | 6.11999 | 33.966 | 56.61 | 56.61 | 33.966 | -550 | 지하1층 | 상위 레벨: 지상 1층 | 10100
2816495 | 지하1층 | 5950 | 4687.85 | 2.8127 | 2.142 | 3.57 | 28.5516 | 16.7352 | -150 | 지하1층 | 상위 레벨: 지상 1층 | 4687.85 | no
2816497 | 지하1층 | 6100 | 13793.5 | 8.27577 | 2.15057 | 3.58428 | 84.1261 | 49.2372 | 0 | 지하1층 | 상위 레벨: 지상 1층 | 13793.5 | no
2816499 | 지하1층 | 5700 | 900 | 0.54 | 3.078 | 5.13 | 5.13 | 3.078 | -400 | 지하1층 | 상위 레벨: 지상 1층 | 1000

# IfcWallStandardCase: 기본 벽:WA111-철근콘크리트구조 벽 500mm_BW1 (9)
Type - PredefinedType: STANDARD; Material: KBIMS-콘크리트 500 mm
Type - ID 데이터 - 단가: 0; 유형 마크: BW1; 유형 이름: WA111-철근콘크리트구조 벽 500mm_BW1
Type - 그래픽 - 거친 축척 채우기 색상: 0
Type - 기타 - 내화구조여부: yes; 주요구조부여부: yes; 카테고리: 벽; KBIMS-부위코드: E275; 조달청표준공사코드: AD; 패밀리 이름: 기본 벽
Type - 시공 - 기능: 외부; 끝단부 마무리: 없음; 인서트 부위 마무리: 마무리하지 않음; 폭: 500 mm
Type - 재료 및 마감재 - 구조 재료: KBIMS-콘크리트
Type - 해석 특성 - 거칠기: 1; 열 저항(R): 0.478011; 열 전달 계수(U): 2.092 kg/K/s3; 열 질량: 755.55; 흡수율: 9290.3
Type - Pset_WallCommon - IsExternal: yes; ThermalTransmittance: 2.092 kg/K/s3
BaseQuantities - Width: 500 mm
ID 데이터 - 연관 있음: yes
공정 - 생성 공정: 새 구성
구속조건 - 베이스 간격띄우기: 0 mm; 매스와 관련됨: no; 룸 경계: yes; 베이스 확장 거리: 0 mm; 벽 베이스가 부착됩니다.: no; 상단 간격띄우기: 0 mm; 상단 확장 거리: 0 mm; 위치선: 구조체 면:외부
구조 - 구조: yes; 구조적 용도: 교좌장치; 보강 철근 피복 - 내부 면: 보강 철근 피복 1 <25 mm>; 보강 철근 피복 - 외부 면: 보강 철근 피복 1 <25 mm>
기타 - 패밀리: 기본 벽; 유형: WA111-철근콘크리트구조 벽 500mm_BW1; 유형 ID: 7626851; 패밀리 및 유형: 기본 벽: WA111-철근콘크리트구조 벽 500mm_BW1
단면형상 정의 - 단면형상: 수직
Pset_QuantityTakeOff - Reference: WA111-철근콘크리트구조 벽 500mm_BW1; sets with these values: 2
Pset_WallCommon - LoadBearing: yes; Reference: WA111-철근콘크리트구조 벽 500mm_BW1
Name (기본 벽:WA111-철근콘크리트구조 벽 500mm_BW1:...) | In | Height (mm) = 미연결 높이 (mm) | Length (mm) | GrossFootprintArea (m2) | GrossVolume (m3) | GrossSideArea (m2) = NetSideArea (m2) = 면적 (m2) | NetVolume (m3) = 체적 (m3) | 베이스 구속조건 | 상단 구속조건 | 상단이 부착됩니다. = ExtendToStructure | 보강 철근 피복 - 다른 면 | 길이 (mm)
2812154 | 지하2층 | 4000 | 4724.62 | 2.34692 | 9.44924 | 18.8985 | 9.38769 | 지하2층 | 상위 레벨: 지하1층 | no | 보강 철근 피복 1 <25 mm> | 4443.84
2812261 | 지하2층 | 4000 | 12430.9 | 6.18466 | 24.7386 | 49.4773 | 24.7115 | 지하2층 | 상위 레벨: 지하1층 | no | 보강 철근 피복 1 <25 mm> | 12369.3
2812376 | 지하2층 | 4000 | 2541.55 | 1.25539 | 5.04187 | 10.0837 | 5.01792 | 지하2층 | 상위 레벨: 지하1층 | no | 보강 철근 피복 1 <25 mm> | 2510.78
2816193 | 지하2층 | 1800 | 17700 | 8.85 | 15.93 | 31.86 | 15.93 | PIT | 상위 레벨: 지하2층 | yes | 보강 철근 피복 1 <25 mm> | 17450
2816195 | 지하2층 | 1800 | 13900 | 6.95 | 12.51 | 25.02 | 12.51 | PIT | 상위 레벨: 지하2층 | no | 보강 철근 피복 1 <25 mm> | 14050
3095890 | 지하2층 | 1800 | 25700 | 12.85 | 23.13 | 46.26 | 23.13 | PIT | 상위 레벨: 지하2층 | no | 보강 철근 피복 1 <25 mm> | 25550
3095892 | 지하2층 | 1800 | 19800 | 9.9 | 17.82 | 35.64 | 17.82 | PIT | 상위 레벨: 지하2층 | no |  | 19953.9
5329936 | 지하2층 | 4000 | 19710 | 9.855 | 39.42 | 78.84 | 39.42 | 지하2층 | 상위 레벨: 지하1층 | no | 보강 철근 피복 1 <25 mm> | 19960
5336341 | 지하1층 | 6100 | 19700 | 9.85 | 60.085 | 120.17 | 58.509 | 지하1층 | 상위 레벨: 지상 1층 | no | 보강 철근 피복 1 <25 mm> | 19950

# IfcWallStandardCase: 기본 벽:WA111-철근콘크리트구조 벽 500mm_BW2 (2)
Type - PredefinedType: STANDARD; Material: KBIMS-콘크리트 500 mm
Type - ID 데이터 - 단가: 0; 유형 마크: BW2; 유형 이름: WA111-철근콘크리트구조 벽 500mm_BW2
Type - 그래픽 - 거친 축척 채우기 색상: 0
Type - 기타 - 내화구조여부: yes; 주요구조부여부: yes; 카테고리: 벽; KBIMS-부위코드: E275; 조달청표준공사코드: AD; 패밀리 이름: 기본 벽
Type - 시공 - 기능: 외부; 끝단부 마무리: 없음; 인서트 부위 마무리: 마무리하지 않음; 폭: 500 mm
Type - 재료 및 마감재 - 구조 재료: KBIMS-콘크리트
Type - 해석 특성 - 거칠기: 1; 열 저항(R): 0.478011; 열 전달 계수(U): 2.092 kg/K/s3; 열 질량: 755.55; 흡수율: 9290.3
Type - Pset_WallCommon - IsExternal: yes; ThermalTransmittance: 2.092 kg/K/s3
BaseQuantities - Width: 500 mm
ID 데이터 - 연관 있음: yes
공정 - 생성 공정: 새 구성
구속조건 - 베이스 간격띄우기: 0 mm; 매스와 관련됨: no; 룸 경계: yes; 베이스 확장 거리: 0 mm; 벽 베이스가 부착됩니다.: no; 상단 간격띄우기: 0 mm; 상단 확장 거리: 0 mm; 상단이 부착됩니다.: no; 위치선: 구조체 면:외부
구조 - 구조: yes; 구조적 용도: 교좌장치; 보강 철근 피복 - 내부 면: 보강 철근 피복 1 <25 mm>; 보강 철근 피복 - 외부 면: 보강 철근 피복 1 <25 mm>
기타 - 패밀리: 기본 벽; 유형: WA111-철근콘크리트구조 벽 500mm_BW2; 유형 ID: 7626805; 패밀리 및 유형: 기본 벽: WA111-철근콘크리트구조 벽 500mm_BW2
단면형상 정의 - 단면형상: 수직
Pset_QuantityTakeOff - Reference: WA111-철근콘크리트구조 벽 500mm_BW2; sets with these values: 2
Pset_WallCommon - LoadBearing: yes; ExtendToStructure: no; Reference: WA111-철근콘크리트구조 벽 500mm_BW2
Name (기본 벽:WA111-철근콘크리트구조 벽 500mm_BW2:...) | In | Height (mm) = 미연결 높이 (mm) | Length (mm) = 길이 (mm) | GrossFootprintArea (m2) | GrossVolume (m3) | GrossSideArea (m2) = NetSideArea (m2) = 면적 (m2) | NetVolume (m3) = 체적 (m3) | 베이스 구속조건 | 상단 구속조건
5329930 | 지하2층 | 4000 | 10680 | 5.34 | 21.36 | 42.72 | 21.36 | 지하2층 | 상위 레벨: 지하1층
5336387 | 지하1층 | 6100 | 10700 | 5.35 | 32.635 | 65.27 | 31.779 | 지하1층 | 상위 레벨: 지상 1층 | 구조 - 보강 철근 피복 - 다른 면: 보강 철근 피복 1 <25 mm>

# IfcWallStandardCase: 기본 벽:WA111-철근콘크리트구조 벽 500mm_BW3 (4)
Type - PredefinedType: STANDARD; Material: KBIMS-콘크리트 500 mm
Type - ID 데이터 - 단가: 0; 유형 마크: BW3; 유형 이름: WA111-철근콘크리트구조 벽 500mm_BW3
Type - 그래픽 - 거친 축척 채우기 색상: 0
Type - 기타 - 내화구조여부: yes; 주요구조부여부: yes; 카테고리: 벽; KBIMS-부위코드: E275; 조달청표준공사코드: AD; 패밀리 이름: 기본 벽
Type - 시공 - 기능: 외부; 끝단부 마무리: 없음; 인서트 부위 마무리: 마무리하지 않음; 폭: 500 mm
Type - 재료 및 마감재 - 구조 재료: KBIMS-콘크리트
Type - 해석 특성 - 거칠기: 1; 열 저항(R): 0.478011; 열 전달 계수(U): 2.092 kg/K/s3; 열 질량: 755.55; 흡수율: 9290.3
Type - Pset_WallCommon - IsExternal: yes; ThermalTransmittance: 2.092 kg/K/s3
BaseQuantities - Width: 500 mm
ID 데이터 - 연관 있음: yes
공정 - 생성 공정: 새 구성
구속조건 - 베이스 간격띄우기: 0 mm; 매스와 관련됨: no; 룸 경계: yes; 베이스 확장 거리: 0 mm; 벽 베이스가 부착됩니다.: no; 상단 확장 거리: 0 mm; 상단이 부착됩니다.: no; 위치선: 구조체 면:외부
구조 - 구조: yes; 보강 철근 피복 - 다른 면: 보강 철근 피복 1 <25 mm>; 구조적 용도: 교좌장치; 보강 철근 피복 - 내부 면: 보강 철근 피복 1 <25 mm>; 보강 철근 피복 - 외부 면: 보강 철근 피복 1 <25 mm>
기타 - 패밀리: 기본 벽; 유형: WA111-철근콘크리트구조 벽 500mm_BW3; 유형 ID: 7626733; 패밀리 및 유형: 기본 벽: WA111-철근콘크리트구조 벽 500mm_BW3
단면형상 정의 - 단면형상: 수직
Pset_QuantityTakeOff - Reference: WA111-철근콘크리트구조 벽 500mm_BW3; sets with these values: 2
Pset_WallCommon - LoadBearing: yes; ExtendToStructure: no; Reference: WA111-철근콘크리트구조 벽 500mm_BW3
Name (기본 벽:WA111-철근콘크리트구조 벽 500mm_BW3:...) | In | Height (mm) = 미연결 높이 (mm) | Length (mm) | GrossFootprintArea (m2) | GrossVolume (m3) | GrossSideArea (m2) = NetSideArea (m2) = 면적 (m2) | NetVolume (m3) = 체적 (m3) | 상단 간격띄우기 (mm) | 베이스 구속조건 | 상단 구속조건 | 길이 (mm)
2812636 | 지하2층 | 4000 | 36400 | 18.2 | 72.7999 | 145.6 | 72.7999 | 0 | 지하2층 | 상위 레벨: 지하1층 | 36400
2812747 | 지하2층 | 4000 | 11710 | 5.855 | 23.42 | 46.84 | 23.42 | 0 | 지하2층 | 상위 레벨: 지하1층 | 11960
2815705 | 지하1층 | 6100 | 12200 | 6.1 | 37.21 | 74.42 | 36.234 | 0 | 지하1층 | 상위 레벨: 지상 1층 | 11950
5337406 | 지하1층 | 4000 | 8400.01 | 4.2 | 16.69 | 33.38 | 16.69 | -2100 | 지하1층 | 상위 레벨: 지상 1층 | 8650.01

# IfcWallStandardCase: 기본 벽:WA111-철근콘크리트구조 벽 500mm_BW4, 기본 벽:WA111-철근콘크리트구조 벽 500mm_BW4:5329910
In: 지하2층
Type - PredefinedType: STANDARD; Material: KBIMS-콘크리트 500 mm
Type - ID 데이터 - 단가: 0; 유형 마크: BW4; 유형 이름: WA111-철근콘크리트구조 벽 500mm_BW4
Type - 그래픽 - 거친 축척 채우기 색상: 0
Type - 기타 - 내화구조여부: yes; 주요구조부여부: yes; 카테고리: 벽; KBIMS-부위코드: E275; 조달청표준공사코드: AD; 패밀리 이름: 기본 벽
Type - 시공 - 기능: 외부; 끝단부 마무리: 없음; 인서트 부위 마무리: 마무리하지 않음; 폭: 500 mm
Type - 재료 및 마감재 - 구조 재료: KBIMS-콘크리트
Type - 해석 특성 - 거칠기: 1; 열 저항(R): 0.478011; 열 전달 계수(U): 2.092 kg/K/s3; 열 질량: 755.55; 흡수율: 9290.3
Type - Pset_WallCommon - IsExternal: yes; ThermalTransmittance: 2.092 kg/K/s3
BaseQuantities - Height: 4000 mm; Length: 17440 mm; Width: 500 mm; GrossFootprintArea: 8.27521 m2; GrossVolume: 34.88 m3; GrossSideArea: 69.76 m2; NetSideArea: 69.76 m2; NetVolume: 33.1008 m3
ID 데이터 - 연관 있음: yes
공정 - 생성 공정: 새 구성
구속조건 - 베이스 간격띄우기: 0 mm; 매스와 관련됨: no; 룸 경계: yes; 베이스 확장 거리: 0 mm; 벽 베이스가 부착됩니다.: no; 상단 간격띄우기: 0 mm; 상단 확장 거리: 0 mm; 베이스 구속조건: 지하2층; 상단 구속조건: 상위 레벨: 지하1층; 상단이 부착됩니다.: no; 위치선: 구조체 면:외부; 미연결 높이: 4000 mm
구조 - 구조: yes; 보강 철근 피복 - 다른 면: 보강 철근 피복 1 <25 mm>; 구조적 용도: 교좌장치; 보강 철근 피복 - 내부 면: 보강 철근 피복 1 <25 mm>; 보강 철근 피복 - 외부 면: 보강 철근 피복 1 <25 mm>
기타 - 패밀리: 기본 벽; 유형: WA111-철근콘크리트구조 벽 500mm_BW4; 유형 ID: 7626681; 패밀리 및 유형: 기본 벽: WA111-철근콘크리트구조 벽 500mm_BW4
단면형상 정의 - 단면형상: 수직
치수 - 길이: 17440 mm; 면적: 69.76 m2; 체적: 33.1008 m3
Pset_QuantityTakeOff - Reference: WA111-철근콘크리트구조 벽 500mm_BW4; sets with these values: 2
Pset_WallCommon - LoadBearing: yes; ExtendToStructure: no; Reference: WA111-철근콘크리트구조 벽 500mm_BW4

# IfcWallStandardCase: 기본 벽:WA111-철근콘크리트구조 벽 500mm_BW5 (2)
In: 지하2층
Type - PredefinedType: STANDARD; Material: KBIMS-콘크리트 500 mm
Type - ID 데이터 - 단가: 0; 유형 마크: BW5; 유형 이름: WA111-철근콘크리트구조 벽 500mm_BW5
Type - 그래픽 - 거친 축척 채우기 색상: 0
Type - 기타 - 내화구조여부: yes; 주요구조부여부: yes; 카테고리: 벽; KBIMS-부위코드: E275; 조달청표준공사코드: AD; 패밀리 이름: 기본 벽
Type - 시공 - 기능: 외부; 끝단부 마무리: 없음; 인서트 부위 마무리: 마무리하지 않음; 폭: 500 mm
Type - 재료 및 마감재 - 구조 재료: KBIMS-콘크리트
Type - 해석 특성 - 거칠기: 1; 열 저항(R): 0.478011; 열 전달 계수(U): 2.092 kg/K/s3; 열 질량: 755.55; 흡수율: 9290.3
Type - Pset_WallCommon - IsExternal: yes; ThermalTransmittance: 2.092 kg/K/s3
BaseQuantities - Height: 4000 mm; Width: 500 mm
ID 데이터 - 연관 있음: yes
공정 - 생성 공정: 새 구성
구속조건 - 베이스 간격띄우기: 0 mm; 매스와 관련됨: no; 룸 경계: yes; 베이스 확장 거리: 0 mm; 벽 베이스가 부착됩니다.: no; 상단 간격띄우기: 0 mm; 상단 확장 거리: 0 mm; 베이스 구속조건: 지하2층; 상단 구속조건: 상위 레벨: 지하1층; 상단이 부착됩니다.: no; 위치선: 구조체 면:외부; 미연결 높이: 4000 mm
구조 - 구조: yes; 구조적 용도: 교좌장치; 보강 철근 피복 - 내부 면: 보강 철근 피복 1 <25 mm>; 보강 철근 피복 - 외부 면: 보강 철근 피복 1 <25 mm>
기타 - 패밀리: 기본 벽; 유형: WA111-철근콘크리트구조 벽 500mm_BW5; 유형 ID: 7626577; 패밀리 및 유형: 기본 벽: WA111-철근콘크리트구조 벽 500mm_BW5
단면형상 정의 - 단면형상: 수직
Pset_QuantityTakeOff - Reference: WA111-철근콘크리트구조 벽 500mm_BW5; sets with these values: 2
Pset_WallCommon - LoadBearing: yes; ExtendToStructure: no; Reference: WA111-철근콘크리트구조 벽 500mm_BW5
Name (기본 벽:WA111-철근콘크리트구조 벽 500mm_BW5:...) | Length (mm) | GrossFootprintArea (m2) | GrossVolume (m3) = NetVolume (m3) = 체적 (m3) | GrossSideArea (m2) = NetSideArea (m2) = 면적 (m2) | 길이 (mm)
2812467 | 6600 | 3.3 | 13.2 | 26.4 | 6950
5329942 | 17695.3 | 8.84767 | 35.3907 | 70.7814 | 17445.3 | 구조 - 보강 철근 피복 - 다른 면: 보강 철근 피복 1 <25 mm>

# IfcWallStandardCase: 기본 벽:WA111-철근콘크리트구조 벽 600mm_DW1, 기본 벽:WA111-철근콘크리트구조 벽 600mm_DW1:5329815
In: 지하2층
Type - PredefinedType: STANDARD; Material: KBIMS-콘크리트 600 mm
Type - ID 데이터 - 단가: 0; 유형 마크: DW1; 유형 이름: WA111-철근콘크리트구조 벽 600mm_DW1
Type - 그래픽 - 거친 축척 채우기 색상: 0
Type - 기타 - 내화구조여부: yes; 주요구조부여부: yes; 카테고리: 벽; KBIMS-부위코드: E275; 조달청표준공사코드: AD; 패밀리 이름: 기본 벽
Type - 시공 - 기능: 외부; 끝단부 마무리: 없음; 인서트 부위 마무리: 마무리하지 않음; 폭: 600 mm
Type - 재료 및 마감재 - 구조 재료: KBIMS-콘크리트
Type - 해석 특성 - 거칠기: 1; 열 저항(R): 0.573614; 열 전달 계수(U): 1.74333 kg/K/s3; 열 질량: 906.66; 흡수율: 9290.3
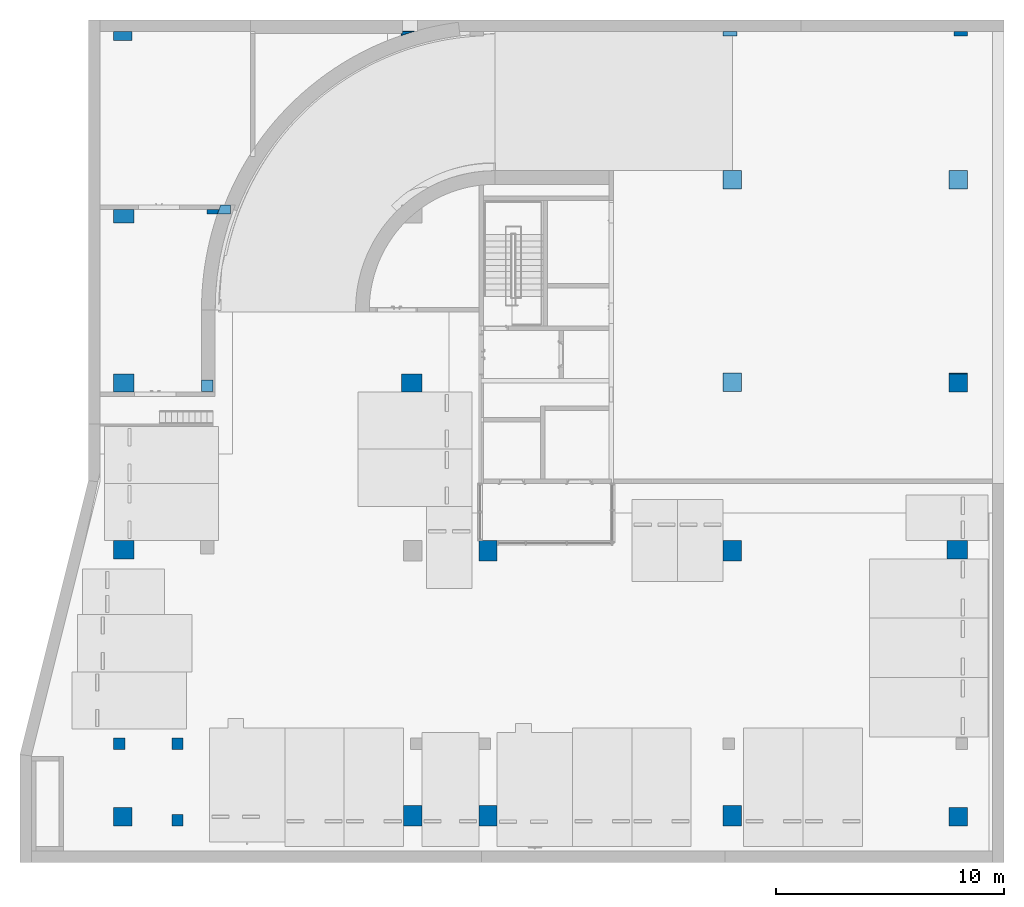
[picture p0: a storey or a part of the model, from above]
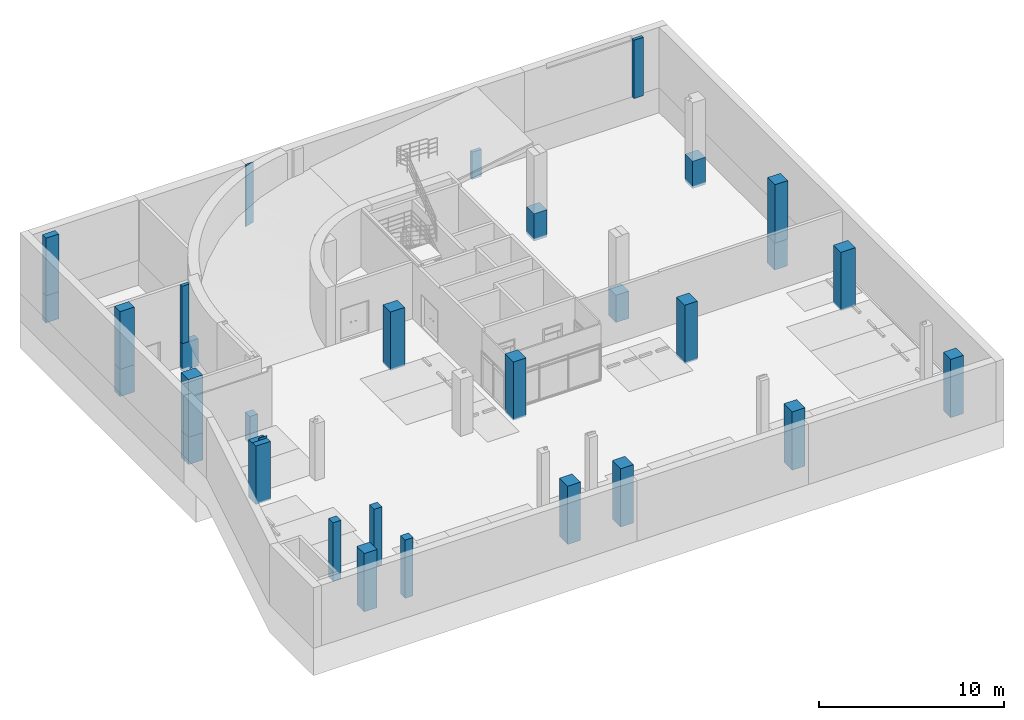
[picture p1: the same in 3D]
Properties of the parts of a building model (IFC2X3), part 39 of 39

# IfcWallStandardCase: 기본 벽:WA111-철근콘크리트구조 벽 600mm_DW1, 기본 벽:WA111-철근콘크리트구조 벽 600mm_DW1:5329815
Type - Pset_WallCommon - IsExternal: yes; ThermalTransmittance: 1.74333 kg/K/s3
BaseQuantities - Height: 4000 mm; Length: 6660 mm; Width: 600 mm; GrossFootprintArea: 3.996 m2; GrossVolume: 15.984 m3; GrossSideArea: 26.64 m2; NetSideArea: 26.64 m2; NetVolume: 15.984 m3
ID 데이터 - 연관 있음: yes
공정 - 생성 공정: 새 구성
구속조건 - 베이스 간격띄우기: 0 mm; 매스와 관련됨: no; 룸 경계: yes; 베이스 확장 거리: 0 mm; 벽 베이스가 부착됩니다.: no; 상단 간격띄우기: 0 mm; 상단 확장 거리: 0 mm; 베이스 구속조건: 지하2층; 상단 구속조건: 상위 레벨: 지하1층; 상단이 부착됩니다.: no; 위치선: 구조체 면:외부; 미연결 높이: 4000 mm
구조 - 구조: yes; 보강 철근 피복 - 다른 면: 보강 철근 피복 1 <25 mm>; 구조적 용도: 교좌장치; 보강 철근 피복 - 내부 면: 보강 철근 피복 1 <25 mm>; 보강 철근 피복 - 외부 면: 보강 철근 피복 1 <25 mm>
기타 - 패밀리: 기본 벽; 유형: WA111-철근콘크리트구조 벽 600mm_DW1; 유형 ID: 7626629; 패밀리 및 유형: 기본 벽: WA111-철근콘크리트구조 벽 600mm_DW1
단면형상 정의 - 단면형상: 수직
치수 - 길이: 6560 mm; 면적: 26.64 m2; 체적: 15.984 m3
Pset_QuantityTakeOff - Reference: WA111-철근콘크리트구조 벽 600mm_DW1; sets with these values: 2
Pset_WallCommon - LoadBearing: yes; ExtendToStructure: no; Reference: WA111-철근콘크리트구조 벽 600mm_DW1

# IfcWallStandardCase: 기본 벽:WA211-시멘트벽돌(일반) 벽 (0.5B) 90mm (103)
Type - PredefinedType: STANDARD; Material: KBIMS-시멘트 벽돌 90 mm
Type - ID 데이터 - 단가: 0; 유형 이름: WA211-시멘트벽돌(일반) 벽 (0.5B) 90mm
Type - 그래픽 - 거친 축척 채우기 색상: 0
Type - 기타 - 카테고리: 벽; KBIMS-부위코드: E24; 불연성재료: 불연재료; 조달청표준공사코드: AFA111010000; 패밀리 이름: 기본 벽
Type - 시공 - 기능: 외부; 끝단부 마무리: 없음; 인서트 부위 마무리: 마무리하지 않음; 폭: 90 mm
Type - 재료 및 마감재 - 구조 재료: KBIMS-시멘트 벽돌
Type - 해석 특성 - 거칠기: 1; 열 저항(R): 0.125; 열 전달 계수(U): 8 kg/K/s3; 열 질량: 136.62; 흡수율: 9290.3
Type - Pset_WallCommon - IsExternal: yes; ThermalTransmittance: 8 kg/K/s3
BaseQuantities - Width: 90 mm
공정 - 생성 공정: 새 구성
구속조건 - 매스와 관련됨: no; 베이스 확장 거리: 0 mm; 벽 베이스가 부착됩니다.: no; 상단 확장 거리: 0 mm; 상단이 부착됩니다.: no
기타 - 패밀리: 기본 벽; 유형: WA211-시멘트벽돌(일반) 벽 (0.5B) 90mm; 유형 ID: 6839214; 패밀리 및 유형: 기본 벽: WA211-시멘트벽돌(일반) 벽 (0.5B) 90mm
단면형상 정의 - 단면형상: 수직
Pset_QuantityTakeOff - Reference: WA211-시멘트벽돌(일반) 벽 (0.5B) 90mm; sets with these values: 2
Pset_WallCommon - ExtendToStructure: no; Reference: WA211-시멘트벽돌(일반) 벽 (0.5B) 90mm
Name (기본 벽:WA211-시멘트벽돌(일반) 벽 (0.5B) 90mm:...) | In | Height (mm) | Length (mm) | GrossFootprintArea (m2) | GrossVolume (m3) | GrossSideArea (m2) = NetSideArea (m2) = 면적 (m2) | NetVolume (m3) = 체적 (m3) | 해설 | 룸 경계 | 베이스 구속조건 | 상단 구속조건 | 미연결 높이 (mm) | 베이스 간격띄우기 (mm) | 상단 간격띄우기 (mm) | 위치선 | 구조 = LoadBearing | 구조적 용도 | 길이 (mm)
3148017 | 지상 1층 | 5110 | 1444.99 | 0.130049 | 0.664551 | 7.38391 | 0.664551 | A | no | 지상 1층 | 상위 레벨: 지상 2층 | 5200 | -600 | -200 | 마감면:내부 | no | 비교좌장치 | 1444.99
3149383 | 지상 2층 | 4350 | 1444.99 | 0.130049 | 0.565714 | 6.28571 | 0.565714 | A | no | 지상 2층 | 상위 레벨: 지상 3층 | 4350 | -50 | -200 | 마감면:내부 | no | 비교좌장치 | 1444.99
3149387 | 지상 3층 | 3950 | 1444.99 | 0.130049 | 0.513694 | 5.70772 | 0.513694 | A | yes | 지상 3층 | 상위 레벨: 지상 4층 | 3950 | -50 | -200 | 마감면:내부 | no | 비교좌장치 | 1544.99
3149391 | 지상 4층 | 3950 | 1444.99 | 0.130049 | 0.513694 | 5.70772 | 0.513694 | A | yes | 지상 4층 | 상위 레벨: 지상 5층 | 3950 | -50 | -200 | 마감면:내부 | no | 비교좌장치 | 1444.99
3149395 | 지상 5층 | 3950 | 1444.99 | 0.130049 | 0.513694 | 5.70772 | 0.513694 | A | no | 지상 5층 | 상위 레벨: 지상 6층 | 3950 | -50 | -200 | 마감면:내부 | no | 비교좌장치 | 1444.99
3149399 | 지상 6층 | 3950 | 1444.99 | 0.130049 | 0.513694 | 5.70772 | 0.513694 | A | no | 지상 6층 | 상위 레벨: 지상 7층 | 3950 | -50 | -200 | 마감면:내부 | no | 비교좌장치 | 1444.99
3149403 | 지상 7층 | 3950 | 1444.99 | 0.130049 | 0.513694 | 5.70772 | 0.513694 | A | no | 지상 7층 | 상위 레벨: 지상 8층 | 3950 | -50 | -200 | 마감면:내부 | no | 비교좌장치 | 1444.99
3149407 | 지상 8층 | 3950 | 1444.99 | 0.130049 | 0.513694 | 5.70772 | 0.513694 | A | no | 지상 8층 | 상위 레벨: 지상 9층 | 3950 | -50 | -200 | 마감면:내부 | no | 비교좌장치 | 1444.99
3149410 | 지상 9층 | 4260 | 800 | 0.072 | 0.30672 | 3.408 | 0.30672 | A | no | 지상 9층 | 상위 레벨: 지상 10층 | 4260 | 40 | -200 | 마감면:내부 | no | 비교좌장치 | 900
3149411 | 지상 9층 | 4350 | 1444.99 | 0.130049 | 0.565714 | 6.28571 | 0.565714 | A | no | 지상 9층 | 상위 레벨: 지상 10층 | 4350 | -50 | -200 | 마감면:내부 | no | 비교좌장치 | 1444.99
3149414 | 지상 10층 | 4810 | 770 | 0.0693 | 0.333333 | 3.7037 | 0.333333 | A | no | 지상 10층 | 상위 레벨: 옥탑층 | 4810 | 40 | -150 | 마감면:내부 | no | 비교좌장치 | 894
3149415 | 지상 10층 | 4900 | 1429.99 | 0.128699 | 0.630626 | 7.00696 | 0.630626 | A | no | 지상 10층 | 상위 레벨: 옥탑층 | 4900 | -50 | -150 | 마감면:내부 | no | 비교좌장치 | 1429.99
3165333 | 지상 1층 | 4300 | 11800 | 1.062 | 0.830888 | 9.23209 | 0.830888 | A | no | 지상 1층 | 상위 레벨: 지상 2층 | 4300 | 0 | -500 | 마감면:외부 | no | 비교좌장치 | 11800
3166408 | 지상 1층 | 4650 | 6599.98 | 0.593998 | 0.671218 | 7.45798 | 0.671218 |  | yes | 지상 1층 | 상위 레벨: 지상 2층 | 4650 | 0 | -150 | 벽 중심선 | no | 비교좌장치 | 6590.98
3166491 | 지상 1층 | 4800 | 2498.17 | 0.224835 | 0.287789 | 3.19766 | 0.287789 |  | yes | 지상 1층 | 상위 레벨: 지상 2층 | 4800 | 0 | 0 | 벽 중심선 | no | 비교좌장치 | 2697.17
3166618 | 지상 1층 | 4800 | 10700 | 0.963002 | 1.23264 | 13.696 | 1.23203 |  | yes | 지상 1층 | 상위 레벨: 지상 2층 | 4800 | 0 | 0 | 벽 중심선 | no | 비교좌장치 | 10691
3166717 | 지상 1층 | 4800 | 10700 | 0.963 | 1.23264 | 13.696 | 1.23264 |  | yes | 지상 1층 | 상위 레벨: 지상 2층 | 4800 | 0 | 0 | 벽 중심선 | no | 비교좌장치 | 10700
3167103 | 지상 1층 | 4650 | 2500.02 | 0.225002 | 0.254252 | 2.82502 | 0.254252 |  | yes | 지상 1층 | 상위 레벨: 지상 2층 | 4800 | 0 | 0 | 벽 중심선 | no | 비교좌장치 | 2590.02
3167156 | 지상 1층 | 4650 | 2500.02 | 0.225002 | 0.254252 | 2.82502 | 0.254252 |  | yes | 지상 1층 | 상위 레벨: 지상 2층 | 4800 | 0 | 0 | 벽 중심선 | no | 비교좌장치 | 2590.02
3167385 | 지상 1층 | 5300 | 2500 | 0.225 | 0.288 | 3.2 | 0.288 |  | yes | 지상 1층 | 상위 레벨: 지상 2층 | 5300 | -500 | 0 | 벽 중심선 | no | 비교좌장치 | 2700
3167450 | 지상 1층 | 4800 | 6492.47 | 0.584322 | 0.747932 | 8.31036 | 0.747932 |  | yes | 지상 1층 | 상위 레벨: 지상 2층 | 4800 | 0 | 0 | 벽 중심선 | no | 비교좌장치 | 6568.66
5343816 | 지하2층 | 3850 | 2500 | 0.225 | 0.3285 | 3.65 | 0.3285 |  | yes | 지하2층 | 상위 레벨: 지하1층 | 4000 | 0 | 0 | 벽 중심선 | no | 비교좌장치 | 2600
5343955 | 지하2층 | 4000 | 2555 | 0.22995 | 0.370219 | 4.11355 | 0.370219 |  | yes | 지하2층 | 상위 레벨: 지하1층 | 4000 | 0 | 0 | 벽 중심선 | no | 비교좌장치 | 2700
5344479 | 지하1층 | 5950 | 2478.11 | 0.22303 | 0.74715 | 8.30166 | 0.74715 |  | yes | 지하1층 | 상위 레벨: GL | 5950 | 0 | 0 | 벽 중심선 | no | 비교좌장치 | 2587.11
5344540 | 지하1층 | 5950 | 5050 | 0.4545 | 1.52258 | 16.9175 | 1.52258 |  | yes | 지하1층 | 상위 레벨: GL | 5950 | 0 | 0 | 벽 중심선 | no | 비교좌장치 | 5050
5344631 | 지하1층 | 6100 | 2551.09 | 0.229598 | 0.803593 | 8.92882 | 0.803593 |  | yes | 지하1층 | 상위 레벨: 지상 1층 | 6100 | 0 | 0 | 벽 중심선 | no | 비교좌장치 | 2696.09
5347520 | 지상 2층 | 4350 | 6600 | 0.594 | 0.79002 | 8.778 | 0.79002 | SSD | yes | 지상 2층 | 상위 레벨: 지상 3층 | 4500 | 0 | 0 | 벽 중심선 | no | 비교좌장치 | 6600
5351826 | 지상 2층 | 4500 | 9900 | 0.891 | 1.31868 | 14.652 | 1.31868 | SSD | yes | 지상 2층 | 상위 레벨: 지상 3층 | 4500 | 0 | 0 | 벽 중심선 | no | 비교좌장치 | 9900
5352045 | 지상 2층 | 4500 | 2499.97 | 0.224998 | 0.332997 | 3.69996 | 0.332997 | SSD | yes | 지상 2층 | 상위 레벨: 지상 3층 | 4500 | 0 | 0 | 벽 중심선 | no | 비교좌장치 | 2499.97
5353459 | 지상 2층 | 4500 | 2200 | 0.198 | 0.29304 | 3.256 | 0.29304 |  | yes | 지상 2층 | 상위 레벨: 지상 3층 | 4500 | 0 | 0 | 벽 중심선 | no | 비교좌장치 | 2155
5353516 | 지상 3층 | 3950 | 2750 | 0.2475 | 0.329175 | 3.6575 | 0.329175 | SSD | yes | 지상 3층 | 상위 레벨: 지상 4층 | 4100 | 0 | 0 | 벽 중심선 | no | 비교좌장치 | 2850
5353543 | 지상 3층 | 3950 | 6600 | 0.594 | 0.79002 | 8.778 | 0.79002 | SSD | yes | 지상 3층 | 상위 레벨: 지상 4층 | 4100 | 0 | 0 | 벽 중심선 | no | 비교좌장치 | 6600
5354023 | 지상 3층 | 4100 | 2498.66 | 0.22488 | 0.329447 | 3.66052 | 0.329447 | SSD | yes | 지상 3층 | 상위 레벨: 지상 4층 | 4100 | 0 | 0 | 벽 중심선 | no | 비교좌장치 | 2498.66
5354050 | 지상 3층 | 4100 | 9900.02 | 0.891002 | 1.31531 | 14.6145 | 1.31531 | SSD | yes | 지상 3층 | 상위 레벨: 지상 4층 | 4100 | 0 | 0 | 벽 중심선 | no | 비교좌장치 | 9900.02
5354231 | 지상 3층 | 4100 | 2195.02 | 0.197552 | 0.292376 | 3.24863 | 0.292376 |  | yes | 지상 3층 | 상위 레벨: 지상 4층 | 4100 | 0 | 0 | 벽 중심선 | no | 비교좌장치 | 2150.02
5354243 | 지상 3층 | 3950 | 2705.01 | 0.243451 | 0.32379 | 3.59766 | 0.32379 |  | yes | 지상 3층 | 상위 레벨: 지상 4층 | 4100 | 0 | 0 | 벽 중심선 | no | 비교좌장치 | 2750.01
5355598 | 지상 4층 | 3950 | 2499.98 | 0.224999 | 0.299248 | 3.32498 | 0.299248 | SSD | yes | 지상 4층 | 상위 레벨: 지상 5층 | 4100 | 0 | 0 | 벽 중심선 | no | 비교좌장치 | 2599.98
5355599 | 지상 4층 | 3950 | 6600 | 0.594 | 0.786645 | 8.7405 | 0.786645 | SSD | yes | 지상 4층 | 상위 레벨: 지상 5층 | 4100 | 0 | 0 | 벽 중심선 | no | 비교좌장치 | 6600
5355601 | 지상 4층 | 4100 | 2500.03 | 0.225003 | 0.333005 | 3.70005 | 0.333005 | SSD | yes | 지상 4층 | 상위 레벨: 지상 5층 | 4100 | 0 | 0 | 벽 중심선 | no | 비교좌장치 | 2500.03
5355602 | 지상 4층 | 4100 | 9900 | 0.891 | 1.31868 | 14.652 | 1.31868 | SSD | yes | 지상 4층 | 상위 레벨: 지상 5층 | 4100 | 0 | 0 | 벽 중심선 | no | 비교좌장치 | 9882
5355603 | 지상 4층 | 4100 | 2195.02 | 0.197552 | 0.292376 | 3.24863 | 0.292376 |  | yes | 지상 4층 | 상위 레벨: 지상 5층 | 4100 | 0 | 0 | 벽 중심선 | no | 비교좌장치 | 2141.02
5355604 | 지상 4층 | 3950 | 2590 | 0.2331 | 0.317259 | 3.5251 | 0.317259 | SSD | yes | 지상 4층 | 상위 레벨: 지상 5층 | 4100 | 0 | 0 | 벽 중심선 | no | 비교좌장치 | 2590
5355605 | 지상 4층 | 3950 | 2705.01 | 0.243451 | 0.320415 | 3.56016 | 0.320415 |  | yes | 지상 4층 | 상위 레벨: 지상 5층 | 4100 | 0 | 0 | 벽 중심선 | no | 비교좌장치 | 2750.01
5355816 | 지상 5층 | 3950 | 2499.99 | 0.224999 | 0.295986 | 3.28874 | 0.295986 | SSD | yes | 지상 5층 | 상위 레벨: 지상 6층 | 4100 | 0 | 0 | 벽 중심선 | no | 비교좌장치 | 2587.99
5355817 | 지상 5층 | 3950 | 6600 | 0.594 | 0.786645 | 8.7405 | 0.786645 | SSD | yes | 지상 5층 | 상위 레벨: 지상 6층 | 4100 | 0 | 0 | 벽 중심선 | no | 비교좌장치 | 6600
5355819 | 지상 5층 | 4100 | 2500.02 | 0.225002 | 0.329627 | 3.66253 | 0.329627 | SSD | yes | 지상 5층 | 상위 레벨: 지상 6층 | 4100 | 0 | 0 | 벽 중심선 | no | 비교좌장치 | 2500.02
5355820 | 지상 5층 | 4100 | 9900.02 | 0.891002 | 1.31531 | 14.6145 | 1.31531 | SSD | yes | 지상 5층 | 상위 레벨: 지상 6층 | 4100 | 0 | 0 | 벽 중심선 | no | 비교좌장치 | 9891.02
5355821 | 지상 5층 | 4100 | 2195.02 | 0.197552 | 0.292376 | 3.24863 | 0.292376 |  | yes | 지상 5층 | 상위 레벨: 지상 6층 | 4100 | 0 | 0 | 벽 중심선 | no | 비교좌장치 | 2150.02
5355822 | 지상 5층 | 3950 | 2594.97 | 0.233547 | 0.307242 | 3.4138 | 0.307242 | SSD | yes | 지상 5층 | 상위 레벨: 지상 6층 | 4100 | 0 | 0 | 벽 중심선 | no | 비교좌장치 | 2594.97
5355823 | 지상 5층 | 3950 | 2705.01 | 0.243451 | 0.320415 | 3.56016 | 0.320415 |  | yes | 지상 5층 | 상위 레벨: 지상 6층 | 4100 | 0 | 0 | 벽 중심선 | no | 비교좌장치 | 2750.01
5356034 | 지상 6층 | 3950 | 2500.01 | 0.225001 | 0.295989 | 3.28876 | 0.295989 | SSD | yes | 지상 6층 | 상위 레벨: 지상 7층 | 4100 | 0 | 0 | 벽 중심선 | no | 비교좌장치 | 2600.01
5356035 | 지상 6층 | 3950 | 6600 | 0.594 | 0.786645 | 8.7405 | 0.786645 | SSD | yes | 지상 6층 | 상위 레벨: 지상 7층 | 4100 | 0 | 0 | 벽 중심선 | no | 비교좌장치 | 6600
5356037 | 지상 6층 | 4100 | 2500 | 0.225 | 0.329625 | 3.6625 | 0.329625 | SSD | yes | 지상 6층 | 상위 레벨: 지상 7층 | 4100 | 0 | 0 | 벽 중심선 | no | 비교좌장치 | 2500
5356038 | 지상 6층 | 4100 | 9900 | 0.891 | 1.31531 | 14.6145 | 1.31531 | SSD | yes | 지상 6층 | 상위 레벨: 지상 7층 | 4100 | 0 | 0 | 벽 중심선 | no | 비교좌장치 | 9882
5356039 | 지상 6층 | 4100 | 2195 | 0.19755 | 0.292374 | 3.2486 | 0.292374 |  | yes | 지상 6층 | 상위 레벨: 지상 7층 | 4100 | 0 | 0 | 벽 중심선 | no | 비교좌장치 | 2141
5356040 | 지상 6층 | 3950 | 2589.98 | 0.233098 | 0.327864 | 3.64293 | 0.327864 | SSD | yes | 지상 6층 | 상위 레벨: 지상 7층 | 4100 | 0 | 0 | 벽 중심선 | no | 비교좌장치 | 2589.98
5356041 | 지상 6층 | 3950 | 2705.01 | 0.243451 | 0.320415 | 3.56016 | 0.320415 |  | yes | 지상 6층 | 상위 레벨: 지상 7층 | 4100 | 0 | 0 | 벽 중심선 | no | 비교좌장치 | 2750.01
5356252 | 지상 7층 | 3950 | 2500 | 0.225 | 0.295988 | 3.28875 | 0.295988 | SSD | yes | 지상 7층 | 상위 레벨: 지상 8층 | 4100 | 0 | 0 | 벽 중심선 | no | 비교좌장치 | 2600
5356253 | 지상 7층 | 3950 | 6600 | 0.594 | 0.786645 | 8.7405 | 0.786645 | SSD | yes | 지상 7층 | 상위 레벨: 지상 8층 | 4100 | 0 | 0 | 벽 중심선 | no | 비교좌장치 | 6600
5356255 | 지상 7층 | 4100 | 2500 | 0.225 | 0.330056 | 3.66729 | 0.330056 | SSD | yes | 지상 7층 | 상위 레벨: 지상 8층 | 4100 | 0 | 0 | 벽 중심선 | no | 비교좌장치 | 2500
5356256 | 지상 7층 | 4100 | 9900 | 0.891 | 1.31531 | 14.6145 | 1.31531 | SSD | yes | 지상 7층 | 상위 레벨: 지상 8층 | 4100 | 0 | 0 | 벽 중심선 | no | 비교좌장치 | 9891
5356257 | 지상 7층 | 4100 | 2195.02 | 0.197552 | 0.292377 | 3.24863 | 0.292377 |  | yes | 지상 7층 | 상위 레벨: 지상 8층 | 4100 | 0 | 0 | 벽 중심선 | no | 비교좌장치 | 2150.02
5356258 | 지상 7층 | 3950 | 2590 | 0.2331 | 0.32787 | 3.643 | 0.32787 | SSD | yes | 지상 7층 | 상위 레벨: 지상 8층 | 4100 | 0 | 0 | 벽 중심선 | no | 비교좌장치 | 2590
5356259 | 지상 7층 | 3950 | 2705.01 | 0.243451 | 0.320415 | 3.56016 | 0.320415 |  | yes | 지상 7층 | 상위 레벨: 지상 8층 | 4100 | 0 | 0 | 벽 중심선 | no | 비교좌장치 | 2750.01
5356470 | 지상 8층 | 3950 | 2500.01 | 0.225001 | 0.295989 | 3.28876 | 0.295989 | SSD | yes | 지상 8층 | 상위 레벨: 지상 9층 | 4100 | 0 | 0 | 벽 중심선 | no | 비교좌장치 | 2588.01
5356471 | 지상 8층 | 3950 | 6800.03 | 0.612003 | 0.810589 | 9.00655 | 0.810589 | SSD | yes | 지상 8층 | 상위 레벨: 지상 9층 | 4100 | 0 | 0 | 벽 중심선 | no | 비교좌장치 | 6800.03
5356473 | 지상 8층 | 4100 | 2500.02 | 0.225002 | 0.329627 | 3.66253 | 0.329627 | SSD | yes | 지상 8층 | 상위 레벨: 지상 9층 | 4100 | 0 | 0 | 벽 중심선 | no | 비교좌장치 | 2500.02
5356474 | 지상 8층 | 4100 | 9999.98 | 0.899998 | 1.32862 | 14.7625 | 1.32862 | SSD | yes | 지상 8층 | 상위 레벨: 지상 9층 | 4100 | 0 | 0 | 벽 중심선 | no | 비교좌장치 | 9981.98
5356475 | 지상 8층 | 4100 | 2295.02 | 0.206552 | 0.305696 | 3.39663 | 0.305696 |  | yes | 지상 8층 | 상위 레벨: 지상 9층 | 4100 | 0 | 0 | 벽 중심선 | no | 비교좌장치 | 2250.02
5356476 | 지상 8층 | 3950 | 2590 | 0.2331 | 0.32787 | 3.643 | 0.32787 | SSD | yes | 지상 8층 | 상위 레벨: 지상 9층 | 4100 | 0 | 0 | 벽 중심선 | no | 비교좌장치 | 2590
5356477 | 지상 8층 | 3950 | 2705.01 | 0.243451 | 0.320415 | 3.56016 | 0.320415 |  | yes | 지상 8층 | 상위 레벨: 지상 9층 | 4100 | 0 | 0 | 벽 중심선 | no | 비교좌장치 | 2750.01
5356689 | 지상 9층 | 4350 | 6800.03 | 0.612003 | 0.810589 | 9.00655 | 0.810589 | SSD | yes | 지상 9층 | 상위 레벨: 지상 10층 | 4500 | 0 | 0 | 벽 중심선 | no | 비교좌장치 | 6800.03
5356691 | 지상 9층 | 4500 | 2590 | 0.2331 | 0.366075 | 4.0675 | 0.366075 | SSD | yes | 지상 9층 | 상위 레벨: 지상 10층 | 4500 | 0 | 0 | 벽 중심선 | no | 비교좌장치 | 2545
5356692 | 지상 9층 | 4500 | 10000 | 0.9 | 1.32863 | 14.7625 | 1.32863 | SSD | yes | 지상 9층 | 상위 레벨: 지상 10층 | 4500 | 0 | 0 | 벽 중심선 | no | 비교좌장치 | 10000
5356693 | 지상 9층 | 4500 | 2295.01 | 0.206551 | 0.305696 | 3.39662 | 0.305696 |  | yes | 지상 9층 | 상위 레벨: 지상 10층 | 4500 | 0 | 0 | 벽 중심선 | no | 비교좌장치 | 2250.01
5356694 | 지상 9층 | 4350 | 2590 | 0.2331 | 0.306648 | 3.4072 | 0.306648 | SSD | yes | 지상 9층 | 상위 레벨: 지상 10층 | 4500 | 0 | 0 | 벽 중심선 | no | 비교좌장치 | 2590
5356695 | 지상 9층 | 4500 | 2705.01 | 0.243451 | 0.356864 | 3.96516 | 0.356864 |  | yes | 지상 9층 | 상위 레벨: 지상 10층 | 4500 | 0 | 0 | 벽 중심선 | no | 비교좌장치 | 2803.38
5367175 | 지상 3층 | 4100 | 6500 | 0.585 | 0.8658 | 9.62 | 0.8658 | SSD | yes | 지상 3층 | 상위 레벨: 지상 4층 | 4100 | 0 | 0 | 벽 중심선 | no | 비교좌장치 | 6500
5369281 | 지상 2층 | 4500 | 6499.97 | 0.584997 | 0.865795 | 9.61995 | 0.865795 | SSD | yes | 지상 2층 | 상위 레벨: 지상 3층 | 4500 | 0 | 0 | 벽 중심선 | no | 비교좌장치 | 6468.72
5382401 | 지상 2층 | 4350 | 2795.01 | 0.251551 | 0.334563 | 3.71736 | 0.334563 |  | yes | 지상 2층 | 상위 레벨: 지상 3층 | 4500 | 0 | 0 | 벽 중심선 | no | 비교좌장치 | 2795.01
5382443 | 지상 2층 | 4350 | 2504.98 | 0.225448 | 0.299846 | 3.33163 | 0.299846 |  | yes | 지상 2층 | 상위 레벨: 지상 3층 | 4500 | 0 | 0 | 벽 중심선 | no | 비교좌장치 | 2594.98
5389253 | 지상 6층 | 3950 | 2795.01 | 0.251551 | 0.331188 | 3.67986 | 0.331188 |  | yes | 지상 6층 | 상위 레벨: 지상 7층 | 4100 | 0 | 0 | 벽 중심선 | no | 비교좌장치 | 2795.01
5389313 | 지상 7층 | 3950 | 2795 | 0.25155 | 0.331187 | 3.67985 | 0.331187 |  | yes | 지상 7층 | 상위 레벨: 지상 8층 | 4100 | 0 | 0 | 벽 중심선 | no | 비교좌장치 | 2795
5389373 | 지상 8층 | 3950 | 2795 | 0.25155 | 0.331187 | 3.67985 | 0.331187 |  | yes | 지상 8층 | 상위 레벨: 지상 9층 | 4100 | 0 | 0 | 벽 중심선 | no | 비교좌장치 | 2795
5393897 | 지상 9층 | 4500 | 6500 | 0.585 | 0.862425 | 9.5825 | 0.862425 | SSD | yes | 지상 9층 | 상위 레벨: 지상 10층 | 4500 | 0 | 0 | 벽 중심선 | no | 비교좌장치 | 6545
5397596 | 지상 4층 | 4100 | 6500 | 0.585 | 0.862425 | 9.5825 | 0.862425 | SSD | yes | 지상 4층 | 상위 레벨: 지상 5층 | 4100 | 0 | 0 | 벽 중심선 | no | 비교좌장치 | 6468.75
5397623 | 지상 5층 | 4100 | 6499.97 | 0.584997 | 0.86242 | 9.58245 | 0.86242 | SSD | yes | 지상 5층 | 상위 레벨: 지상 6층 | 4100 | 0 | 0 | 벽 중심선 | no | 비교좌장치 | 6468.72
5397650 | 지상 6층 | 4100 | 6499.97 | 0.584997 | 0.86242 | 9.58245 | 0.86242 | SSD | yes | 지상 6층 | 상위 레벨: 지상 7층 | 4100 | 0 | 0 | 벽 중심선 | no | 비교좌장치 | 6468.72
5397677 | 지상 7층 | 4100 | 6499.97 | 0.584997 | 0.863599 | 9.59555 | 0.863599 | SSD | yes | 지상 7층 | 상위 레벨: 지상 8층 | 4100 | 0 | 0 | 벽 중심선 | no | 비교좌장치 | 6468.72
5397704 | 지상 8층 | 4100 | 6500 | 0.585 | 0.862425 | 9.5825 | 0.862425 | SSD | yes | 지상 8층 | 상위 레벨: 지상 9층 | 4100 | 0 | 0 | 벽 중심선 | no | 비교좌장치 | 6468.75
5476646 | 지상 1층 | 4400 | 9900 | 0.891 | 0.78408 | 8.712 | 0.78408 | A | no | 지상 1층 | 상위 레벨: 지상 2층 | 4400 | 0 | -400 | 마감면:외부 | no | 비교좌장치 | 9900
5863898 | 지하2층 | 4000 | 4949.99 | 0.445499 | 1.6974 | 18.86 | 1.6974 | -2CW1 | yes | 지하2층 | 상위 레벨: 지하1층 | 4000 | 0 | 0 | 마감면:내부 | yes | 교좌장치 | 5199.99 | ID 데이터 - 연관 있음: yes; 구조 - 보강 철근 피복 - 다른 면: 보강 철근 피복 1 <25 mm>; 보강 철근 피복 - 내부 면: 보강 철근 피복 1 <25 mm>; 보강 철근 피복 - 외부 면: 보강 철근 피복 1 <25 mm>
5909199 | 지상 2층 | 4100 | 2750 | 0.2475 | 0.2673 | 2.97 | 0.2673 | SSD | yes | 지상 2층 | 상위 레벨: 지상 3층 | 4100 | 0 | -400 | 벽 중심선 | no | 비교좌장치 | 2850
5909229 | 지상 9층 | 4100 | 2750 | 0.2475 | 0.263925 | 2.9325 | 0.263925 | SSD | yes | 지상 9층 | 상위 레벨: 지상 10층 | 4100 | 0 | -400 | 벽 중심선 | no | 비교좌장치 | 2850
7703442 | 지상 1층 | 5110 | 800 | 0.072 | 0.36792 | 4.088 | 0.36792 | A | no | 지상 1층 | 상위 레벨: 지상 2층 | 5110 | -510 | -200 | 마감면:내부 | no | 비교좌장치 | 900
7703445 | 지상 2층 | 4260 | 800 | 0.072 | 0.30672 | 3.408 | 0.30672 | A | no | 지상 2층 | 상위 레벨: 지상 3층 | 4260 | 40 | -200 | 마감면:내부 | no | 비교좌장치 | 900
7703448 | 지상 3층 | 3860 | 800 | 0.072 | 0.27792 | 3.088 | 0.27792 | A | no | 지상 3층 | 상위 레벨: 지상 4층 | 3860 | 40 | -200 | 마감면:내부 | no | 비교좌장치 | 900
7703451 | 지상 4층 | 3860 | 800 | 0.072 | 0.27792 | 3.088 | 0.27792 | A | no | 지상 4층 | 상위 레벨: 지상 5층 | 3860 | 40 | -200 | 마감면:내부 | no | 비교좌장치 | 900
7703454 | 지상 5층 | 3860 | 800 | 0.072 | 0.27792 | 3.088 | 0.27792 | A | no | 지상 5층 | 상위 레벨: 지상 6층 | 3860 | 40 | -200 | 마감면:내부 | no | 비교좌장치 | 900
7703457 | 지상 6층 | 3860 | 800 | 0.072 | 0.27792 | 3.088 | 0.27792 | A | no | 지상 6층 | 상위 레벨: 지상 7층 | 3860 | 40 | -200 | 마감면:내부 | no | 비교좌장치 | 900
7703460 | 지상 7층 | 3860 | 800 | 0.072 | 0.27792 | 3.088 | 0.27792 | A | no | 지상 7층 | 상위 레벨: 지상 8층 | 3860 | 40 | -200 | 마감면:내부 | no | 비교좌장치 | 900
7703463 | 지상 8층 | 3860 | 800 | 0.072 | 0.27792 | 3.088 | 0.27792 | A | no | 지상 8층 | 상위 레벨: 지상 9층 | 3860 | 40 | -200 | 마감면:내부 | no | 비교좌장치 | 900
7796598 | 지상 1층 | 4650 | 3874.98 | 0.348748 | 0.394086 | 4.37873 | 0.394086 |  | yes | 지상 1층 | 상위 레벨: 지상 2층 | 4650 | 0 | -150 | 벽 중심선 | no | 비교좌장치 | 3837.48

# IfcWallStandardCase: 기본 벽:WA313-화강석잔다듬 벽 (30, 건식50) 80mm (64)
Type - PredefinedType: STANDARD; Material: KBIMS-화강석 잔다듬 80 mm
Type - ID 데이터 - 단가: 0; 유형 이름: WA313-화강석잔다듬 벽 (30, 건식50) 80mm
Type - 그래픽 - 거친 축척 채우기 색상: 0
Type - 기타 - 카테고리: 벽; KBIMS-부위코드: E24; 불연성재료: 불연재료; 조달청표준공사코드: AMB161A; 패밀리 이름: 기본 벽
Type - 시공 - 기능: 외부; 끝단부 마무리: 없음; 인서트 부위 마무리: 마무리하지 않음; 폭: 80 mm
Type - 해석 특성 - 거칠기: 1; 흡수율: 9290.3
Type - Pset_WallCommon - IsExternal: yes
BaseQuantities - Width: 80 mm
공정 - 생성 공정: 새 구성
구속조건 - 매스와 관련됨: no; 베이스 확장 거리: 0 mm; 벽 베이스가 부착됩니다.: no; 상단 확장 거리: 0 mm; 상단이 부착됩니다.: no; 위치선: 마감면:외부
구조 - 구조: no; 구조적 용도: 비교좌장치
기타 - 패밀리: 기본 벽; 유형: WA313-화강석잔다듬 벽 (30, 건식50) 80mm; 유형 ID: 7431676; 패밀리 및 유형: 기본 벽: WA313-화강석잔다듬 벽 (30, 건식50) 80mm
단면형상 정의 - 단면형상: 수직
Pset_QuantityTakeOff - Reference: WA313-화강석잔다듬 벽 (30, 건식50) 80mm; sets with these values: 2
Pset_WallCommon - LoadBearing: no; ExtendToStructure: no; Reference: WA313-화강석잔다듬 벽 (30, 건식50) 80mm
Name (기본 벽:WA313-화강석잔다듬 벽 (30, 건식50) 80mm:...) | In | Height (mm) | Length (mm) | GrossFootprintArea (m2) | GrossVolume (m3) | GrossSideArea (m2) | NetSideArea (m2) = 면적 (m2) | NetVolume (m3) = 체적 (m3) | 베이스 간격띄우기 (mm) | 룸 경계 | 상단 간격띄우기 (mm) | 베이스 구속조건 | 상단 구속조건 | 미연결 높이 (mm) | 길이 (mm)
2830676 | 지상 1층 | 4800 | 35430 | 2.8344 | 12.5944 | 157.43 | 70.486 | 5.63888 | 0 | no | 0 | 지상 1층 | 상위 레벨: 지상 2층 | 4800 | 35315 | ID 데이터 - 해설: A
2831445 | 지상 1층 | 5200 | 1700.01 | 0.136001 | 0.707204 | 8.84005 | 6.01206 | 0.480965 | -550 | yes | 0 | 지상 1층 | 상위 레벨: 지상 2층 | 5350 | 1620.01
2831526 | 지상 1층 | 5350 | 1170 | 0.0936 | 0.48852 | 6.1065 | 6.1065 | 0.48852 | -550 | yes | 0 | 지상 1층 | 상위 레벨: 지상 2층 | 5350 | 1135
2834832 | 지상 2층 | 4580 | 35430 | 2.8344 | 12.9816 | 162.269 | 68.7014 | 5.49611 | 0 | yes | 80 | 지상 2층 | 상위 레벨: 지상 3층 | 4580 | 35315 | ID 데이터 - 해설: A
2834833 | 지상 2층 | 4580 | 37480 | 2.9984 | 1.35583 | 16.9479 | 76.9524 | 6.15619 | 0 | yes | 80 | 지상 2층 | 상위 레벨: 지상 3층 | 4580 | 37480
2834834 | 지상 2층 | 4580 | 28700 | 2.296 | 10.5157 | 131.446 | 55.3305 | 4.42644 | 0 | yes | 80 | 지상 2층 | 상위 레벨: 지상 3층 | 4580 | 28780
2834835 | 지상 2층 | 4580 | 10855 | 0.8684 | 3.97727 | 49.7159 | 21.7281 | 1.73825 | 0 | yes | 80 | 지상 2층 | 상위 레벨: 지상 3층 | 4580 | 10855
2834838 | 지상 2층 | 4500 | 1250 | 0.1 | 0.45 | 5.625 | 5.625 | 0.45 | 0 | yes | 0 | 지상 2층 | 상위 레벨: 지상 3층 | 4500 | 1135
2835456 | 지상 3층 | 2620 | 898 | 0.07184 | 0.188221 | 2.35276 | 2.35276 | 0.188221 | 80 | yes | -1400 | 지상 3층 | 상위 레벨: 지상 4층 | 2620 | 849
2835460 | 지상 3층 | 4100 | 1170 | 0.0936 | 0.38376 | 4.797 | 4.797 | 0.38376 | 0 | yes | 0 | 지상 3층 | 상위 레벨: 지상 4층 | 4100 | 1135
2835472 | 지상 4층 | 4100 | 1250 | 0.1 | 0.41 | 5.125 | 5.125 | 0.41 | 0 | yes | 0 | 지상 4층 | 상위 레벨: 지상 5층 | 4100 | 1135
2835484 | 지상 5층 | 4100 | 1170 | 0.0936 | 0.38376 | 4.797 | 4.797 | 0.38376 | 0 | yes | 0 | 지상 5층 | 상위 레벨: 지상 6층 | 4100 | 1135
2835496 | 지상 6층 | 4100 | 1250 | 0.1 | 0.41 | 5.125 | 5.125 | 0.41 | 0 | yes | 0 | 지상 6층 | 상위 레벨: 지상 7층 | 4100 | 1135
2835508 | 지상 7층 | 4100 | 1170 | 0.0936 | 0.38376 | 4.797 | 4.797 | 0.38376 | 0 | yes | 0 | 지상 7층 | 상위 레벨: 지상 8층 | 4100 | 1135
2835520 | 지상 8층 | 4100 | 1250 | 0.1 | 0.41 | 5.125 | 5.125 | 0.41 | 0 | yes | 0 | 지상 8층 | 상위 레벨: 지상 9층 | 4100 | 1135
2835532 | 지상 9층 | 4500 | 1170 | 0.0936 | 0.4212 | 5.265 | 5.265 | 0.4212 | 0 | yes | 0 | 지상 9층 | 상위 레벨: 지상 10층 | 4500 | 1135
2843567 | 지상 1층 | 4800 | 13580 | 1.0864 | 5.21472 | 65.184 | 23.296 | 1.86368 | 0 | yes | 0 | 지상 1층 | 상위 레벨: 지상 2층 | 4800 | 13580
2843673 | 지상 1층 | 4650 | 900 | 0.072 | 0.3348 | 4.185 | 4.185 | 0.3348 | 0 | yes | 0 | 지상 1층 | 상위 레벨: 지상 2층 | 4800 | 940
2861497 | 지상 1층 | 3520 | 11792 | 0.94336 | 3.32063 | 41.5078 | 41.5078 | 3.32063 | 80 | yes | -1200 | 지상 1층 | 상위 레벨: 지상 2층 | 3520 | 11792 | ID 데이터 - 해설: SSD; 마크: 17
2890564 | 옥탑층 | 4700 | 5700 | 0.456 | 2.1432 | 26.79 | 26.79 | 2.1432 | 0 | yes | 700 | 옥탑층 | 상위 레벨: 지붕층 | 4700 | 5735
2890971 | 옥탑층 | 4700 | 7899.99 | 0.631999 | 2.9704 | 37.13 | 34.57 | 2.7656 | 0 | yes | 700 | 옥탑층 | 상위 레벨: 지붕층 | 4700 | 7899.99
2891284 | 옥탑층 | 4700 | 6980 | 0.5584 | 2.62448 | 32.806 | 32.806 | 2.62448 | 0 | yes | 700 | 옥탑층 | 상위 레벨: 지붕층 | 4700 | 6980
2891447 | 옥탑층 | 4700 | 10981.8 | 0.878547 | 4.12917 | 51.6146 | 43.0346 | 3.44277 | 0 | yes | 700 | 옥탑층 | 상위 레벨: 지붕층 | 4700 | 10981.8
2891632 | 옥탑층 | 4700 | 12600 | 1.008 | 4.7376 | 59.22 | 53.42 | 4.2736 | 0 | yes | 700 | 옥탑층 | 상위 레벨: 지붕층 | 4700 | 12715
2990425 | 옥탑층 | 1300 | 2604.99 | 0.208399 | 0.270919 | 3.38649 | 3.38649 | 0.270919 | 0 | yes | -2700 | 옥탑층 | 상위 레벨: 지붕층 | 1300 | 2564.99
2991193 | 옥탑층 | 1300 | 950 | 0.076 | 0.0988 | 1.235 | 1.235 | 0.0988 | 0 | yes | -2700 | 옥탑층 | 상위 레벨: 지붕층 | 1300 | 1065
3119097 | 지상 1층 | 1420 | 2380.02 | 0.190401 | 0.27037 | 3.37962 | 3.37962 | 0.27037 | 0 | yes | 0 | 지상 1층 | 상위 레벨: 지상 2층 | 4800 | 2420.02
3177772 | 지상 1층 | 4600 | 2594.99 | 0.207599 | 0.954957 | 11.937 | 11.937 | 0.954957 | 200 | yes | 0 | 지상 1층 | 상위 레벨: 지상 2층 | 4600 | 2634.99
3177986 | 지상 2층 | 4500 | 2604.99 | 0.208399 | 0.937797 | 11.7225 | 11.7225 | 0.937797 | 0 | yes | 0 | 지상 2층 | 상위 레벨: 지상 3층 | 4500 | 2564.99
3177989 | 지상 3층 | 4100 | 2604.99 | 0.208399 | 0.854437 | 10.6805 | 10.6805 | 0.854437 | 0 | yes | 0 | 지상 3층 | 상위 레벨: 지상 4층 | 4100 | 2564.99
3177992 | 지상 4층 | 4100 | 2604.99 | 0.208399 | 0.854437 | 10.6805 | 10.6805 | 0.854437 | 0 | yes | 0 | 지상 4층 | 상위 레벨: 지상 5층 | 4100 | 2564.99
3177995 | 지상 5층 | 4100 | 2604.99 | 0.208399 | 0.854437 | 10.6805 | 10.6805 | 0.854437 | 0 | yes | 0 | 지상 5층 | 상위 레벨: 지상 6층 | 4100 | 2564.99
3177998 | 지상 6층 | 4100 | 2604.99 | 0.208399 | 0.854437 | 10.6805 | 10.6805 | 0.854437 | 0 | yes | 0 | 지상 6층 | 상위 레벨: 지상 7층 | 4100 | 2564.99
3178001 | 지상 7층 | 4100 | 2604.99 | 0.208399 | 0.854437 | 10.6805 | 10.6805 | 0.854437 | 0 | yes | 0 | 지상 7층 | 상위 레벨: 지상 8층 | 4100 | 2564.99
3178004 | 지상 8층 | 4100 | 2604.99 | 0.208399 | 0.854437 | 10.6805 | 10.6805 | 0.854437 | 0 | yes | 0 | 지상 8층 | 상위 레벨: 지상 9층 | 4100 | 2564.99
3178007 | 지상 9층 | 4500 | 2604.99 | 0.208399 | 0.937797 | 11.7225 | 11.7225 | 0.937797 | 0 | yes | 0 | 지상 9층 | 상위 레벨: 지상 10층 | 4500 | 2564.99
3178693 | 지상 2층 | 4500 | 2200 | 0.176 | 0.7788 | 9.735 | 9.735 | 0.7788 | 0 | yes | 0 | 지상 2층 | 상위 레벨: 지상 3층 | 4500 | 2200
3179029 | 지상 1층 | 5350 | 2200 | 0.176 | 0.92936 | 11.617 | 11.617 | 0.92936 | -550 | yes | 0 | 지상 1층 | 상위 레벨: 지상 2층 | 5350 | 2200
3179032 | 지상 3층 | 4100 | 2200 | 0.176 | 0.7084 | 8.855 | 8.855 | 0.7084 | 0 | yes | 0 | 지상 3층 | 상위 레벨: 지상 4층 | 4100 | 2200
3179035 | 지상 4층 | 4100 | 2200 | 0.176 | 0.7084 | 8.855 | 8.855 | 0.7084 | 0 | yes | 0 | 지상 4층 | 상위 레벨: 지상 5층 | 4100 | 2200
3179038 | 지상 5층 | 4100 | 2200 | 0.176 | 0.7084 | 8.855 | 8.855 | 0.7084 | 0 | yes | 0 | 지상 5층 | 상위 레벨: 지상 6층 | 4100 | 2200
3179041 | 지상 6층 | 4100 | 2200 | 0.176 | 0.7084 | 8.855 | 8.855 | 0.7084 | 0 | yes | 0 | 지상 6층 | 상위 레벨: 지상 7층 | 4100 | 2200
3179044 | 지상 7층 | 4100 | 2200 | 0.176 | 0.7084 | 8.855 | 8.855 | 0.7084 | 0 | yes | 0 | 지상 7층 | 상위 레벨: 지상 8층 | 4100 | 2200
3179047 | 지상 8층 | 4100 | 2200 | 0.176 | 0.7084 | 8.855 | 8.855 | 0.7084 | 0 | yes | 0 | 지상 8층 | 상위 레벨: 지상 9층 | 4100 | 2200
3179050 | 지상 9층 | 4500 | 2200 | 0.176 | 0.7788 | 9.735 | 9.735 | 0.7788 | 0 | yes | 0 | 지상 9층 | 상위 레벨: 지상 10층 | 4500 | 2200
3180763 | 지상 2층 | 850 | 1540.01 | 0.123201 | 0.104721 | 1.30901 | 1.30901 | 0.104721 | -850 | yes | 0 | 지상 2층 | 상위 레벨: 지상 2층 | 850 | 1620.01
3181007 | 지상 3층 | 600 | 1540.01 | 0.123201 | 0.0739204 | 0.924005 | 0.924005 | 0.0739204 | -600 | yes | 0 | 지상 3층 | 상위 레벨: 지상 3층 | 600 | 1620.01
3181095 | 지상 4층 | 600 | 1540.01 | 0.123201 | 0.0739204 | 0.924005 | 0.924005 | 0.0739204 | -600 | yes | 0 | 지상 4층 | 상위 레벨: 지상 4층 | 600 | 1620.01
3181158 | 지상 5층 | 600 | 1540.01 | 0.123201 | 0.0739204 | 0.924005 | 0.924005 | 0.0739204 | -600 | yes | 0 | 지상 5층 | 상위 레벨: 지상 5층 | 600 | 1620.01
3181160 | 지상 6층 | 600 | 1540.01 | 0.123201 | 0.0739204 | 0.924005 | 0.924005 | 0.0739204 | -600 | yes | 0 | 지상 6층 | 상위 레벨: 지상 6층 | 600 | 1620.01
3181162 | 지상 7층 | 600 | 1540.01 | 0.123201 | 0.0739204 | 0.924005 | 0.924005 | 0.0739204 | -600 | yes | 0 | 지상 7층 | 상위 레벨: 지상 7층 | 600 | 1620.01
3181164 | 지상 8층 | 600 | 1540.01 | 0.123201 | 0.0739204 | 0.924005 | 0.924005 | 0.0739204 | -600 | yes | 0 | 지상 8층 | 상위 레벨: 지상 8층 | 600 | 1620.01
3181166 | 지상 9층 | 600 | 1540.01 | 0.123201 | 0.0739204 | 0.924005 | 0.924005 | 0.0739204 | -600 | yes | 0 | 지상 9층 | 상위 레벨: 지상 9층 | 600 | 1620.01
3181168 | 지상 10층 | 600 | 1540.01 | 0.123201 | 0.0739204 | 0.924005 | 0.924005 | 0.0739204 | -600 | yes | 0 | 지상 10층 | 상위 레벨: 지상 10층 | 600 | 1620.01
3181194 | 옥탑층 | 600 | 1540.01 | 0.123201 | 0.0739204 | 0.924005 | 0.924005 | 0.0739204 | -600 | yes | 0 | 옥탑층 | 상위 레벨: 옥탑층 | 600 | 1835.01
3181684 | 지상 2층 | 4350 | 1540.01 | 0.123201 | 0.535923 | 6.69904 | 4.07302 | 0.325842 | 0 | yes | 0 | 지상 2층 | 상위 레벨: 지상 3층 | 4500 | 1620.01
3181709 | 지상 3층 | 3950 | 1620.01 | 0.129601 | 0.511923 | 6.39903 | 3.87403 | 0.309923 | 0 | yes | 0 | 지상 3층 | 상위 레벨: 지상 4층 | 4100 | 1620.01
3181730 | 지상 4층 | 3950 | 1540.01 | 0.123201 | 0.486643 | 6.08303 | 3.55803 | 0.284643 | 0 | yes | 0 | 지상 4층 | 상위 레벨: 지상 5층 | 4100 | 1620.01
3181751 | 지상 5층 | 3950 | 1620.01 | 0.129601 | 0.511923 | 6.39903 | 3.77302 | 0.301841 | 0 | yes | 0 | 지상 5층 | 상위 레벨: 지상 6층 | 4100 | 1620.01
3181772 | 지상 6층 | 3950 | 1540.01 | 0.123201 | 0.486643 | 6.08303 | 3.45702 | 0.276561 | 0 | yes | 0 | 지상 6층 | 상위 레벨: 지상 7층 | 4100 | 1620.01
3181793 | 지상 7층 | 3950 | 1620.01 | 0.129601 | 0.511923 | 6.39903 | 3.77302 | 0.301841 | 0 | yes | 0 | 지상 7층 | 상위 레벨: 지상 8층 | 4100 | 1760.01
3181814 | 지상 8층 | 3950 | 1540.01 | 0.123201 | 0.486643 | 6.08303 | 3.45702 | 0.276561 | 0 | yes | 0 | 지상 8층 | 상위 레벨: 지상 9층 | 4100 | 1620.01
3181835 | 지상 9층 | 4350 | 1620.01 | 0.129601 | 0.563763 | 7.04704 | 4.42102 | 0.353682 | 0 | yes | 0 | 지상 9층 | 상위 레벨: 지상 10층 | 4500 | 1620.01
5352195 | 지상 1층 | 4650 | 900 | 0.072 | 0.3348 | 4.185 | 4.185 | 0.3348 | 0 | yes | 0 | 지상 1층 | 상위 레벨: 지상 2층 | 4800 | 940

# IfcWallStandardCase: 기본 벽:WA731-DRY WALL(C50, GS12.5mm) (1겹한면, GW50mm) 62.5mm (57)
Type - PredefinedType: STANDARD; Material: KBIMS-DRY WALL 12.5 mm, KBIMS-경량철골벽틀 50 mm
Type - ID 데이터 - 단가: 0; 유형 이름: WA731-DRY WALL(C50, GS12.5mm) (1겹한면, GW50mm) 62.5mm
Type - 그래픽 - 거친 축척 채우기 색상: 0
Type - 기타 - 카테고리: 벽; KBIMS-부위코드: E24; 경계벽: yes; 불연성재료: 불연재료; 조달청표준공사코드: AOC700010000; 패밀리 이름: 기본 벽
Type - 시공 - 기능: 내부; 끝단부 마무리: 없음; 인서트 부위 마무리: 마무리하지 않음; 폭: 62.5 mm
Type - 해석 특성 - 거칠기: 1; 열 저항(R): 0.0192308; 열 전달 계수(U): 52 kg/K/s3; 열 질량: 11.55; 흡수율: 9290.3
Type - Pset_WallCommon - IsExternal: no; ThermalTransmittance: 52 kg/K/s3
BaseQuantities - Width: 62.5 mm
공정 - 생성 공정: 새 구성
구속조건 - 매스와 관련됨: no; 룸 경계: yes; 베이스 확장 거리: 0 mm; 벽 베이스가 부착됩니다.: no; 상단 확장 거리: 0 mm; 상단이 부착됩니다.: no; 위치선: 구조체 면:내부
구조 - 구조: no; 구조적 용도: 비교좌장치
기타 - 패밀리: 기본 벽; 유형: WA731-DRY WALL(C50, GS12.5mm) (1겹한면, GW50mm) 62.5mm; 유형 ID: 6840292; 패밀리 및 유형: 기본 벽: WA731-DRY WALL(C50, GS12.5mm) (1겹한면, GW50mm) 62.5mm
단면형상 정의 - 단면형상: 수직
Pset_QuantityTakeOff - Reference: WA731-DRY WALL(C50, GS12.5mm) (1겹한면, GW50mm) 62.5mm; sets with these values: 2
Pset_WallCommon - LoadBearing: no; ExtendToStructure: no; Reference: WA731-DRY WALL(C50, GS12.5mm) (1겹한면, GW50mm) 62.5mm
Name (기본 벽:WA731-DRY WALL(C50, GS12.5mm) (1겹한면, GW50mm) 62.5mm:...) | In | Height (mm) | Length (mm) | GrossFootprintArea (m2) | GrossVolume (m3) = NetVolume (m3) = 체적 (m3) | GrossSideArea (m2) = NetSideArea (m2) = 면적 (m2) | 베이스 간격띄우기 (mm) | 베이스 구속조건 | 상단 구속조건 | 미연결 높이 (mm) | 상단 간격띄우기 (mm) | 길이 (mm)
2831868 | 지상 1층 | 3700 | 13285 | 0.830313 | 3.07106 | 49.137 | 0 | 지상 1층 | 상위 레벨: 지상 2층 | 3700 | -1100 | 13392.5
2832990 | 지상 1층 | 3620 | 11700 | 0.73125 | 2.64713 | 42.354 | 0 | 지상 1층 | 상위 레벨: 지상 2층 | 3700 | -1100 | 11700
2833112 | 지상 1층 | 3700 | 13248.1 | 0.828007 | 3.06363 | 49.018 | 0 | 지상 1층 | 상위 레벨: 지상 2층 | 3700 | -1100 | 13248.1
2833197 | 지상 1층 | 3700 | 13500 | 0.843749 | 3.12187 | 49.9499 | 0 | 지상 1층 | 상위 레벨: 지상 2층 | 3700 | -1100 | 13500
2833295 | 지상 1층 | 3700 | 13138.1 | 0.821134 | 3.0382 | 48.6111 | 0 | 지상 1층 | 상위 레벨: 지상 2층 | 3700 | -1100 | 13138.1
2833375 | 지상 1층 | 3700 | 13193.1 | 0.824571 | 3.05091 | 48.8146 | 0 | 지상 1층 | 상위 레벨: 지상 2층 | 3700 | -1100 | 13193.1
2833454 | 지상 1층 | 3700 | 12192.5 | 0.762031 | 2.81952 | 45.1123 | 0 | 지상 1층 | 상위 레벨: 지상 2층 | 3700 | -1100 | 12192.5
2833545 | 지상 1층 | 3700 | 10037.5 | 0.627343 | 2.32117 | 37.1387 | 0 | 지상 1층 | 상위 레벨: 지상 2층 | 3700 | -1100 | 10068.7
2833642 | 지상 1층 | 3700 | 10037.5 | 0.627343 | 2.32117 | 37.1387 | 0 | 지상 1층 | 상위 레벨: 지상 2층 | 3700 | -1100 | 10068.7
2833730 | 지상 1층 | 5200 | 10375 | 0.648439 | 3.37188 | 53.9501 | -1500 | 지상 1층 | 상위 레벨: 지상 2층 | 5200 | -1100 | 10475
2833820 | 지상 1층 | 5200 | 10337.5 | 0.646095 | 3.35969 | 53.7551 | -1500 | 지상 1층 | 상위 레벨: 지상 2층 | 5200 | -1100 | 10437.5
2834643 | 지상 1층 | 3580 | 10683 | 0.667686 | 2.39032 | 38.2451 | 0 | 지상 1층 | 상위 레벨: 지상 2층 | 3580 | -1220 | 10692
2834970 | 지상 2층 | 3300 | 11900 | 0.74375 | 2.45438 | 39.27 | 0 | 지상 2층 | 상위 레벨: 지상 3층 | 3300 | -1200 | 11900
2834972 | 지상 2층 | 3300 | 13285 | 0.830312 | 2.74003 | 43.8405 | 0 | 지상 2층 | 상위 레벨: 지상 3층 | 3300 | -1200 | 13392.5
2834975 | 지상 2층 | 3300 | 11655 | 0.728438 | 2.40384 | 38.4615 | 0 | 지상 2층 | 상위 레벨: 지상 3층 | 3300 | -1200 | 11655
2834980 | 지상 2층 | 3300 | 10882 | 0.680125 | 2.24441 | 35.9106 | 0 | 지상 2층 | 상위 레벨: 지상 3층 | 3300 | -1200 | 10891
2835147 | 지상 3층 | 3100 | 12600 | 0.7875 | 2.44125 | 39.06 | 0 | 지상 3층 | 상위 레벨: 지상 4층 | 3100 | -1000 | 12600
2835148 | 지상 3층 | 3100 | 13410 | 0.838125 | 2.59819 | 41.571 | 0 | 지상 3층 | 상위 레벨: 지상 4층 | 3100 | -1000 | 13495
2835149 | 지상 3층 | 3100 | 11900 | 0.74375 | 2.30563 | 36.89 | 0 | 지상 3층 | 상위 레벨: 지상 4층 | 3100 | -1000 | 11900
2835150 | 지상 3층 | 3100 | 10900 | 0.68125 | 2.11188 | 33.79 | 0 | 지상 3층 | 상위 레벨: 지상 4층 | 3100 | -1000 | 10900
2835152 | 지상 3층 | 3100 | 10882 | 0.680125 | 2.10839 | 33.7342 | 0 | 지상 3층 | 상위 레벨: 지상 4층 | 3100 | -1000 | 10891
2835262 | 지상 4층 | 3100 | 11900 | 0.74375 | 2.30563 | 36.89 | 0 | 지상 4층 | 상위 레벨: 지상 5층 | 3100 | -1000 | 11900
2835263 | 지상 4층 | 3100 | 13410 | 0.838125 | 2.59819 | 41.571 | 0 | 지상 4층 | 상위 레벨: 지상 5층 | 3100 | -1000 | 13530
2835264 | 지상 4층 | 3100 | 11900 | 0.74375 | 2.30563 | 36.89 | 0 | 지상 4층 | 상위 레벨: 지상 5층 | 3100 | -1000 | 11900
2835265 | 지상 4층 | 2980 | 10900 | 0.68125 | 2.03013 | 32.482 | 0 | 지상 4층 | 상위 레벨: 지상 5층 | 2980 | -1120 | 10900
2835267 | 지상 4층 | 3100 | 10900 | 0.68125 | 2.11188 | 33.79 | 0 | 지상 4층 | 상위 레벨: 지상 5층 | 3100 | -1000 | 10900
2835383 | 지상 5층 | 3100 | 11900 | 0.74375 | 2.30563 | 36.89 | 0 | 지상 5층 | 상위 레벨: 지상 6층 | 3100 | -1000 | 11900
2835384 | 지상 5층 | 3100 | 13410.6 | 0.838161 | 2.5983 | 41.5728 | 0 | 지상 5층 | 상위 레벨: 지상 6층 | 3100 | -1000 | 13530.6
2835385 | 지상 5층 | 3100 | 11900 | 0.74375 | 2.30563 | 36.89 | 0 | 지상 5층 | 상위 레벨: 지상 6층 | 3100 | -1000 | 11900
2835386 | 지상 5층 | 3100 | 10900 | 0.68125 | 2.11188 | 33.79 | 0 | 지상 5층 | 상위 레벨: 지상 6층 | 3100 | -1000 | 10900
2835388 | 지상 5층 | 3100 | 10900 | 0.68125 | 2.11188 | 33.79 | 0 | 지상 5층 | 상위 레벨: 지상 6층 | 3100 | -1000 | 10900
2835391 | 지상 6층 | 3100 | 11900 | 0.74375 | 2.30563 | 36.89 | 0 | 지상 6층 | 상위 레벨: 지상 7층 | 3100 | -1000 | 11900
2835393 | 지상 6층 | 3100 | 11900 | 0.743749 | 2.30562 | 36.8899 | 0 | 지상 6층 | 상위 레벨: 지상 7층 | 3100 | -1000 | 11900
2835394 | 지상 6층 | 3100 | 10900 | 0.68125 | 2.11188 | 33.79 | 0 | 지상 6층 | 상위 레벨: 지상 7층 | 3100 | -1000 | 10900
2835396 | 지상 6층 | 3100 | 10900 | 0.68125 | 2.11188 | 33.79 | 0 | 지상 6층 | 상위 레벨: 지상 7층 | 3100 | -1000 | 10900
2835399 | 지상 7층 | 3100 | 11900 | 0.74375 | 2.30563 | 36.89 | 0 | 지상 7층 | 상위 레벨: 지상 8층 | 3100 | -1000 | 11900
2835401 | 지상 7층 | 3100 | 11900 | 0.743749 | 2.30562 | 36.8899 | 0 | 지상 7층 | 상위 레벨: 지상 8층 | 3100 | -1000 | 11900
2835402 | 지상 7층 | 3100 | 10900 | 0.68125 | 2.11188 | 33.79 | 0 | 지상 7층 | 상위 레벨: 지상 8층 | 3100 | -1000 | 10900
2835404 | 지상 7층 | 3100 | 10900 | 0.68125 | 2.11188 | 33.79 | 0 | 지상 7층 | 상위 레벨: 지상 8층 | 3100 | -1000 | 10900
2835407 | 지상 8층 | 3100 | 12800 | 0.8 | 2.48 | 39.68 | 0 | 지상 8층 | 상위 레벨: 지상 9층 | 3100 | -1000 | 12875
2835408 | 지상 8층 | 3100 | 13410 | 0.838125 | 2.59819 | 41.571 | 0 | 지상 8층 | 상위 레벨: 지상 9층 | 3100 | -1000 | 13530
2835409 | 지상 8층 | 3100 | 12100 | 0.75625 | 2.34438 | 37.51 | 0 | 지상 8층 | 상위 레벨: 지상 9층 | 3100 | -1000 | 12100
2835410 | 지상 8층 | 3100 | 11100 | 0.69375 | 2.15063 | 34.41 | 0 | 지상 8층 | 상위 레벨: 지상 9층 | 3100 | -1000 | 11100
2835412 | 지상 8층 | 3100 | 11100 | 0.69375 | 2.15063 | 34.41 | 0 | 지상 8층 | 상위 레벨: 지상 9층 | 3100 | -1000 | 11100
2835415 | 지상 9층 | 3200 | 12100 | 0.75625 | 2.42 | 38.72 | 0 | 지상 9층 | 상위 레벨: 지상 10층 | 3200 | -1300 | 12100
2835417 | 지상 9층 | 3200 | 12100 | 0.75625 | 2.42 | 38.72 | 0 | 지상 9층 | 상위 레벨: 지상 10층 | 3200 | -1300 | 12100
2835418 | 지상 9층 | 3200 | 11100 | 0.69375 | 2.22 | 35.52 | 0 | 지상 9층 | 상위 레벨: 지상 10층 | 3200 | -1300 | 11100
2835420 | 지상 9층 | 3200 | 11100 | 0.69375 | 2.22 | 35.52 | 0 | 지상 9층 | 상위 레벨: 지상 10층 | 3200 | -1300 | 11100
5382246 | 지상 2층 | 3300 | 7537.49 | 0.471093 | 1.55121 | 24.8194 | 0 | 지상 2층 | 상위 레벨: 지상 3층 | 3300 | -1200 | 7537.49
5389060 | 지상 4층 | 3100 | 7704.99 | 0.481562 | 1.49284 | 23.8855 | 0 | 지상 4층 | 상위 레벨: 지상 5층 | 3100 | -1000 | 7754.99
5389062 | 지상 5층 | 3100 | 7705 | 0.481563 | 1.49203 | 23.8724 | 0 | 지상 5층 | 상위 레벨: 지상 6층 | 3100 | -1000 | 7780
5389063 | 지상 6층 | 3100 | 7705 | 0.481563 | 1.49284 | 23.8855 | 0 | 지상 6층 | 상위 레벨: 지상 7층 | 3100 | -1000 | 7780
5389064 | 지상 7층 | 3100 | 7705 | 0.481563 | 1.49284 | 23.8855 | 0 | 지상 7층 | 상위 레벨: 지상 8층 | 3100 | -1000 | 7780
5389065 | 지상 8층 | 3100 | 7705 | 0.481563 | 1.49284 | 23.8855 | 0 | 지상 8층 | 상위 레벨: 지상 9층 | 3100 | -1000 | 7780
5392901 | 지상 9층 | 3200 | 7704.99 | 0.481562 | 1.541 | 24.656 | 0 | 지상 9층 | 상위 레벨: 지상 10층 | 3200 | -1300 | 7779.99
5406055 | 지상 3층 | 3100 | 7650 | 0.478125 | 1.474 | 23.584 | 0 | 지상 3층 | 상위 레벨: 지상 4층 | 3100 | -1000 | 7650
5459039 | 지상 2층 | 3300 | 11901 | 0.743812 | 2.45458 | 39.2733 | 0 | 지상 2층 | 상위 레벨: 지상 3층 | 3300 | -1200 | 11901

# IfcWallStandardCase: 기본 벽:WA921-목재 걸레받이 (H45*24mm, 라왕, 바니쉬), 기본 벽:WA921-목재 걸레받이 (H45*24mm, 라왕, 바니쉬):7364969
In: 지상 2층
Type - PredefinedType: STANDARD; Material: KBIMS-목재 걸레받이 (라왕, 바니쉬) 24 mm
Type - ID 데이터 - 단가: 0; 유형 이름: WA921-목재 걸레받이 (H45*24mm, 라왕, 바니쉬)
Type - 그래픽 - 거친 축척 채우기 색상: 0
Type - 기타 - 카테고리: 벽; KBIMS-부위코드: E24; 조달청표준공사코드: AOA53; 패밀리 이름: 기본 벽
Type - 시공 - 기능: 외부; 끝단부 마무리: 없음; 인서트 부위 마무리: 마무리하지 않음; 폭: 24 mm
Type - 해석 특성 - 거칠기: 1; 흡수율: 9290.3
Type - Pset_WallCommon - IsExternal: yes
BaseQuantities - Height: 45 mm; Length: 3000 mm; Width: 24 mm; GrossFootprintArea: 0.072 m2; GrossVolume: 0.00324 m3; GrossSideArea: 0.135 m2; NetSideArea: 0.135 m2; NetVolume: 0.00324 m3
공정 - 생성 공정: 새 구성
구속조건 - 베이스 간격띄우기: 0 mm; 매스와 관련됨: no; 룸 경계: yes; 베이스 확장 거리: 0 mm; 벽 베이스가 부착됩니다.: no; 상단 간격띄우기: 0 mm; 상단 확장 거리: 0 mm; 위치선: 벽 중심선; 상단이 부착됩니다.: no; 베이스 구속조건: 지상 2층; 미연결 높이: 45 mm
구조 - 구조: no; 구조적 용도: 비교좌장치
기타 - 패밀리: 기본 벽; 유형: WA921-목재 걸레받이 (H45*24mm, 라왕, 바니쉬); 유형 ID: 7364970; 패밀리 및 유형: 기본 벽: WA921-목재 걸레받이 (H45*24mm, 라왕, 바니쉬)
단면형상 정의 - 단면형상: 수직
치수 - 길이: 3000 mm; 면적: 0.135 m2; 체적: 0.00324 m3
Pset_QuantityTakeOff - Reference: WA921-목재 걸레받이 (H45*24mm, 라왕, 바니쉬); sets with these values: 2
Pset_WallCommon - LoadBearing: no; ExtendToStructure: no; Reference: WA921-목재 걸레받이 (H45*24mm, 라왕, 바니쉬)

# IfcWindow: WD733-그릴창(알루미늄):WD733-그릴창(알루미늄)_600x800mm (28)
Type - ParameterTakesPrecedence: no; Sizeable: no; Material: <Unnamed> (16)
Type - ID 데이터 - 유형 마크: 24; 유형 이름: WD733-그릴창(알루미늄)_600x800mm; 유형 해설: ST
Type - 기타 - 카테고리: 창; 방화여부: yes; KBIMS-부위코드: E334; 조달청표준공사코드: ALB167900000; 패널유형: single; 패밀리 이름: WD733-그릴창(알루미늄)
Type - 시공 - 벽 마무리: 호스트별
Type - 치수 - 구조체 간격: 0 mm; A: 25 mm; B: 50 mm; 높이: 800 mm; 대략적인 높이: 800 mm; 대략적인 폭: 600 mm; 중심이동: 25 mm; 패널 두께: 95 mm; 패널수: 15; 패널 폭: 510 mm; 폭: 600 mm; 프레임 두께: 150 mm; 프레임 폭: 45 mm
Type - 해석 특성 - 열 특성 정의 기준: 개략적 유형; 해석 시공: <없음>
Type - Pset_WindowCommon - IsExternal: no
OverallHeight: 800 mm; OverallWidth: 600 mm
Pset_QuantityTakeOff - Reference: WD733-그릴창(알루미늄)_600x800mm
Pset_WindowCommon - Reference: WD733-그릴창(알루미늄)_600x800mm
BaseQuantities - Height: 800 mm; Width: 600 mm; Area: 0.48 m2
공정 - 생성 공정: 새 구성
기타 - 유형: WD733-그릴창(알루미늄)_600x800mm; 유형 ID: 7459609; 창의개폐비: 50; 패밀리: WD733-그릴창(알루미늄); 패밀리 및 유형: WD733-그릴창(알루미늄): WD733-그릴창(알루미늄)_600x800mm
치수 - 면적: 2.12048 m2; 체적: 0.0208362 m3
Name (WD733-그릴창(알루미늄):WD733-그릴창(알루미늄)_600x800mm:...) | In | 레벨 | 씰 높이 (mm) | 헤드 높이 (mm) | 호스트 ID | Material
2976935 | 지상 2층 | 지상 2층 | 500 | 1300 | 2820040 | Pset_WindowCommon - IsExternal: yes
2979348 | 지상 2층 | 지상 2층 | 500 | 1300 | 2820040
2979508 | 지상 1층 | 지상 1층 | 500 | 1300 | 2818055 | <Unnamed>
2979509 | 지상 1층 | 지상 1층 | 500 | 1300 | 2818055 | <Unnamed>
2979600 | 지상 3층 | 지상 3층 | 500 | 1300 | 2820459 | <Unnamed>
2979601 | 지상 3층 | 지상 3층 | 500 | 1300 | 2820459 | <Unnamed>
2979692 | 지상 4층 | 지상 4층 | 500 | 1300 | 2820709 | <Unnamed>
2979693 | 지상 4층 | 지상 4층 | 500 | 1300 | 2820709 | <Unnamed>
2979784 | 지상 5층 | 지상 5층 | 500 | 1300 | 2821211 | <Unnamed>
2979785 | 지상 5층 | 지상 5층 | 500 | 1300 | 2821211 | <Unnamed>
2979876 | 지상 6층 | 지상 6층 | 500 | 1300 | 2821471 | <Unnamed>
2979877 | 지상 6층 | 지상 6층 | 500 | 1300 | 2821471 | <Unnamed>
2979968 | 지상 7층 | 지상 7층 | 500 | 1300 | 2821667 | <Unnamed>
2979969 | 지상 7층 | 지상 7층 | 500 | 1300 | 2821667 | <Unnamed>
2980060 | 지상 8층 | 지상 8층 | 500 | 1300 | 2822013 | <Unnamed>
2980061 | 지상 8층 | 지상 8층 | 500 | 1300 | 2822013 | <Unnamed>
2980152 | 지상 9층 | 지상 9층 | 500 | 1300 | 2822219 | <Unnamed>
2980153 | 지상 9층 | 지상 9층 | 500 | 1300 | 2822219 | <Unnamed>
2980244 | 지상 10층 | 지상 10층 | 500 | 1300 | 2822405
2980245 | 지상 10층 | 지상 10층 | 500 | 1300 | 2822405
2980336 | 지하1층 | 지하1층 | 500 | 1300 | 2816479
2980337 | 지하1층 | 지하1층 | 500 | 1300 | 2816479
2980428 | 지하2층 | 지하2층 | 500 | 1300 | 2813950 | <Unnamed>
2980429 | 지하2층 | 지하2층 | 500 | 1300 | 2813950 | <Unnamed>
3190340 | 지상 1층 | 지상 1층 | 2000 | 2800 | 2818061 | <Unnamed>
3190516 | 지상 1층 | 지상 1층 | 2000 | 2800 | 2818061 | <Unnamed>
3190889 | 지상 1층 | 지상 1층 | 2000 | 2800 | 3157421 | <Unnamed>
3190927 | 지상 1층 | 지상 1층 | 2000 | 2800 | 3157421 | <Unnamed>

# IfcWindow: WD812-미들창(스테인리스 스틸):WD812-미들창(스테인리스 스틸) 하부개폐 1000x1600mm (15)
Type - ParameterTakesPrecedence: no; Sizeable: no; Material: KBIMS-스테인리스 스틸 (3), KBIMS-유리 (2)
Type - ID 데이터(Type) - copyleft: archfool.com; OmniClass 번호: 23.30.20.00; OmniClass 제목: Windows; 설명: WD812; 유형 마크: 52; 유형 이름: WD812-미들창(스테인리스 스틸) 하부개폐 1000x1600mm; 유형 해설: 21x22
Type - 그래픽(Type) - 상부개폐: no; 우측개폐: no; 좌측개폐: no; 하부개폐: yes; 회전형_상하/좌우: no
Type - 기타(Type) - 카테고리: 창; KBIMS_보급정보-보급코드: bSK-191231; KBIMS_보급정보-저작자: (사)빌딩스마트협회; KBIMS_식별-버전: 1.03; KBIMS-부위코드: E334; 건설정보분류체계-부위분류: E334; 조달청표준공사코드: ALB230; 조달청표준공사코드-세부공종: ALB230; 패널유형: double; 패밀리 이름: WD812-미들창(스테인리스 스틸)
Type - 시공(Type) - 벽 마무리: 호스트별
Type - 재료 및 마감재(Type) - 창틀 재료: KBIMS-스테인리스 스틸; 패널 재료: KBIMS-유리; 프레임 재료: KBIMS-스테인리스 스틸
Type - 치수(Type) - 구조체 간격: 0 mm; 높이: 1600 mm; 높이_상부창(고정): 1000 mm; 높이_하부창: 600 mm; 대략적인 높이: 1600 mm; 대략적인 폭: 1000 mm; 씰높이: 800 mm; 유리창 폭: 880 mm; 중심이동_유리 상부: 0 mm; 중심이동_유리창 하부: 45 mm; 중심이동_창틀: 0 mm; 창틀 두께: 120 mm; 창틀 폭: 60 mm; 패널 두께: 12 mm; 폭: 1000 mm; 프레임 두께: 30 mm; 프레임 폭: 50 mm
Type - 해석 특성(Type) - 열 특성 정의 기준: 개략적 유형; 해석 시공: <없음>
Type - Pset_WindowCommon - IsExternal: no
OverallHeight: 1600 mm; OverallWidth: 1000 mm
Pset_QuantityTakeOff - Reference: WD812-미들창(스테인리스 스틸) 하부개폐 1000x1600mm
Pset_WindowCommon - Reference: WD812-미들창(스테인리스 스틸) 하부개폐 1000x1600mm
BaseQuantities - Height: 1600 mm; Width: 1000 mm; Area: 1.6 m2
공정 - 생성 공정: 새 구성
기타 - 유형: WD812-미들창(스테인리스 스틸) 하부개폐 1000x1600mm; 유형 ID: 7464744; 카테고리: 창; 패밀리: WD812-미들창(스테인리스 스틸); 패밀리 및 유형: WD812-미들창(스테인리스 스틸): WD812-미들창(스테인리스 스틸) 하부개폐 1000x1600mm; 창의개폐비: 50
치수 - 면적: 2.46752 m2; 벽체 opening 면적: 1.6 m2; 체적: 0.0593112 m3
Name (WD812-미들창(스테인리스 스틸):WD812-미들창(스테인리스 스틸) 하부개폐 1000x1600mm:...) | In | 레벨 | 씰 높이 (mm) | 호스트 ID | 헤드 높이 (mm) | Material
5438115 | 지상 3층 | 지상 3층 | 3030 | 2820441 | 4630 | Pset_WindowCommon - IsExternal: yes
5438282 | 지상 4층 | 지상 4층 | 3030 | 2820691 | 4630 | KBIMS-스테인리스 스틸, KBIMS-유리
5438284 | 지상 5층 | 지상 5층 | 3030 | 2821193 | 4630 | KBIMS-스테인리스 스틸, KBIMS-유리
5438286 | 지상 6층 | 지상 6층 | 3030 | 2821453 | 4630 | KBIMS-스테인리스 스틸, KBIMS-유리
5438288 | 지상 7층 | 지상 7층 | 3030 | 2821649 | 4630 | KBIMS-스테인리스 스틸, KBIMS-유리
5438290 | 지상 8층 | 지상 8층 | 3030 | 2821995 | 4630 | KBIMS-스테인리스 스틸, KBIMS-유리
5438364 | 지상 2층 | 지상 2층 | 3030 | 2820022 | 4630 | KBIMS-스테인리스 스틸, KBIMS-유리
5458777 | 지상 1층 | 지상 1층 | 3600 | 2818037 | 5200 | KBIMS-스테인리스 스틸, KBIMS-유리
5458793 | 지상 9층 | 지상 9층 | 3415.8 | 2822201 | 5015.8 | KBIMS-스테인리스 스틸, KBIMS-유리
5458810 | 지상 10층 | 지상 10층 | 3919.8 | 2822387 | 5519.8
5458824 | 옥탑층 | 옥탑층 | 1200 | 2822815 | 2800 | KBIMS-스테인리스 스틸, KBIMS-유리
5458834 | 옥탑층 | 옥탑층 | 1200 | 2822815 | 2800 | KBIMS-스테인리스 스틸, KBIMS-유리
5458852 | 옥탑층 | 옥탑층 | 1200 | 2822813 | 2800 | KBIMS-스테인리스 스틸, KBIMS-유리
5458861 | 옥탑층 | 옥탑층 | 1200 | 2822841 | 2800 | KBIMS-스테인리스 스틸, KBIMS-유리
8084605 | 옥탑층 | 옥탑층 | 1200 | 2822815 | 2800 | KBIMS-스테인리스 스틸, KBIMS-유리 | ID 데이터 - 마크: 58

# IfcWindow: WD812-미들창(스테인리스 스틸):WD812-미들창(스테인리스 스틸) 하부개폐 800x1200mm (11)
Type - ParameterTakesPrecedence: no; Sizeable: no; Material: KBIMS-스테인리스 스틸 (3), KBIMS-유리 (2)
Type - ID 데이터(Type) - copyleft: archfool.com; OmniClass 번호: 23.30.20.00; OmniClass 제목: Windows; 설명: WD812; 유형 마크: 51; 유형 이름: WD812-미들창(스테인리스 스틸) 하부개폐 800x1200mm; 유형 해설: 21x22
Type - 그래픽(Type) - 상부개폐: no; 우측개폐: no; 좌측개폐: no; 하부개폐: yes; 회전형_상하/좌우: no
Type - 기타(Type) - 카테고리: 창; KBIMS_보급정보-보급코드: bSK-191231; KBIMS_보급정보-저작자: (사)빌딩스마트협회; KBIMS_식별-버전: 1.03; KBIMS-부위코드: E334; 건설정보분류체계-부위분류: E334; 조달청표준공사코드: ALB230; 조달청표준공사코드-세부공종: ALB230; 패널유형: double; 패밀리 이름: WD812-미들창(스테인리스 스틸)
Type - 시공(Type) - 벽 마무리: 호스트별
Type - 재료 및 마감재(Type) - 창틀 재료: KBIMS-스테인리스 스틸; 패널 재료: KBIMS-유리; 프레임 재료: KBIMS-스테인리스 스틸
Type - 치수(Type) - 구조체 간격: 0 mm; 중심이동_유리 상부: 0 mm; 중심이동_창틀: 0 mm; 높이: 1200 mm; 높이_상부창(고정): 600 mm; 높이_하부창: 600 mm; 대략적인 높이: 1200 mm; 대략적인 폭: 800 mm; 씰높이: 800 mm; 유리창 폭: 680 mm; 중심이동_유리창 하부: 45 mm; 창틀 두께: 120 mm; 창틀 폭: 60 mm; 패널 두께: 12 mm; 폭: 800 mm; 프레임 두께: 30 mm; 프레임 폭: 50 mm
Type - 해석 특성(Type) - 열 특성 정의 기준: 개략적 유형; 해석 시공: <없음>
Type - Pset_WindowCommon - IsExternal: no
OverallHeight: 1200 mm; OverallWidth: 800 mm
Pset_QuantityTakeOff - Reference: WD812-미들창(스테인리스 스틸) 하부개폐 800x1200mm
Pset_WindowCommon - Reference: WD812-미들창(스테인리스 스틸) 하부개폐 800x1200mm
BaseQuantities - Height: 1200 mm; Width: 800 mm; Area: 0.96 m2
공정 - 생성 공정: 새 구성
기타 - 카테고리: 창; 패밀리: WD812-미들창(스테인리스 스틸); 유형: WD812-미들창(스테인리스 스틸) 하부개폐 800x1200mm; 유형 ID: 7464739; 패밀리 및 유형: WD812-미들창(스테인리스 스틸): WD812-미들창(스테인리스 스틸) 하부개폐 800x1200mm; 창의개폐비: 50
치수 - 면적: 1.62992 m2; 벽체 opening 면적: 0.96 m2; 체적: 0.0421992 m3
Name (WD812-미들창(스테인리스 스틸):WD812-미들창(스테인리스 스틸) 하부개폐 800x1200mm:...) | In | 레벨 | 씰 높이 (mm) | 호스트 ID | 헤드 높이 (mm) | Material
5438394 | 지상 3층 | 지상 3층 | 1200 | 2820441 | 2400 | Pset_WindowCommon - IsExternal: yes
5458593 | 지상 1층 | 지상 1층 | 400 | 2818037 | 1600 | KBIMS-스테인리스 스틸, KBIMS-유리
5458595 | 지상 2층 | 지상 2층 | 1200 | 2820022 | 2400 | KBIMS-스테인리스 스틸, KBIMS-유리
5458597 | 지상 4층 | 지상 4층 | 1200 | 2820691 | 2400 | KBIMS-스테인리스 스틸, KBIMS-유리
5458599 | 지상 5층 | 지상 5층 | 1200 | 2821193 | 2400 | KBIMS-스테인리스 스틸, KBIMS-유리
5458601 | 지상 6층 | 지상 6층 | 1200 | 2821453 | 2400 | KBIMS-스테인리스 스틸, KBIMS-유리
5458603 | 지상 7층 | 지상 7층 | 1200 | 2821649 | 2400 | KBIMS-스테인리스 스틸, KBIMS-유리
5458605 | 지상 8층 | 지상 8층 | 1200 | 2821995 | 2400 | KBIMS-스테인리스 스틸, KBIMS-유리
5458607 | 지상 9층 | 지상 9층 | 1200 | 2822201 | 2400 | KBIMS-스테인리스 스틸, KBIMS-유리
5458609 | 지상 10층 | 지상 10층 | 1200 | 7720721 | 2400
5458870 | 옥탑층 | 옥탑층 | 1200 | 2822821 | 2400 | KBIMS-스테인리스 스틸, KBIMS-유리

# IfcWindow: WD842-2단 하부 더블 프로젝트 창(스테인리스 스틸):WD842-2단 하부 더블 프로젝트 창(스테인리스 스틸)_1500x1600mm (10)
Type - ParameterTakesPrecedence: no; Sizeable: no; Material: KBIMS-스테인리스 스틸_도금 (4), KBIMS-유리 (3)
Type - ID 데이터(Type) - OmniClass 번호: 23.30.20.00; OmniClass 제목: Windows; 유형 마크: 53; 유형 이름: WD842-2단 하부 더블 프로젝트 창(스테인리스 스틸)_1500x1600mm; 유형 해설: AW
Type - 그래픽(Type) - 상부개폐: no; 우측개폐: no; 좌측개폐: no; 회전형_상하/좌우: no; 하부개폐: no
Type - 기타(Type) - 카테고리: 창; 방화여부: yes; KBIMS-부위코드: E334; 조달청표준공사코드: ALB230; 패널유형: triple; 패밀리 이름: WD842-2단 하부 더블 프로젝트 창(스테인리스 스틸)
Type - 시공(Type) - 벽 마무리: 호스트별
Type - 재료 및 마감재(Type) - 창틀 재료: KBIMS-스테인리스 스틸_도금; 패널 재료: KBIMS-유리; 프레임 재료: KBIMS-스테인리스 스틸_도금
Type - 치수(Type) - 구조체 간격: 0 mm; 중심이동_창틀: 0 mm; 중심이동_패널 상부: 0 mm; 높이: 1600 mm; 높이_상부창(고정): 1100 mm; 높이_하부창: 500 mm; 대략적인 높이: 1600 mm; 대략적인 폭: 1500 mm; 중심이동_패널 하부: 45 mm; 창틀 두께: 125 mm; 창틀 폭: 60 mm; 패널 두께: 12 mm; 폭: 1500 mm; 프레임 두께: 30 mm; 프레임 폭: 50 mm
Type - 해석 특성(Type) - 열 특성 정의 기준: 개략적 유형; 해석 시공: <없음>
Type - Pset_WindowCommon - IsExternal: no
OverallHeight: 1600 mm; OverallWidth: 1500 mm
Pset_QuantityTakeOff - Reference: WD842-2단 하부 더블 프로젝트 창(스테인리스 스틸)_1500x1600mm
Pset_WindowCommon - Reference: WD842-2단 하부 더블 프로젝트 창(스테인리스 스틸)_1500x1600mm
BaseQuantities - Height: 1600 mm; Width: 1500 mm; Area: 2.4 m2
공정 - 생성 공정: 새 구성
구속조건 - 씰 높이: 1000 mm
기타 - 카테고리: 창; 패밀리: WD842-2단 하부 더블 프로젝트 창(스테인리스 스틸); 유형: WD842-2단 하부 더블 프로젝트 창(스테인리스 스틸)_1500x1600mm; 유형 ID: 7468499; 패밀리 및 유형: WD842-2단 하부 더블 프로젝트 창(스테인리스 스틸): WD842-2단 하부 더블 프로젝트 창(스테인리스 스틸)_1500x1600mm; 창의개폐비: 100; 헤드 높이: 2600 mm
치수 - 면적: 3.60783 m2; 체적: 0.084837 m3
Name (WD842-2단 하부 더블 프로젝트 창(스테인리스 스틸):WD842-2단 하부 더블 프로젝트 창(스테인리스 스틸)_1500x1600mm:...) | In | 레벨 | 호스트 ID | Material
5433475 | 지상 4층 | 지상 4층 | 5999125 | Pset_WindowCommon - IsExternal: yes
5433523 | 지상 1층 | 지상 1층 | 5342341
5433525 | 지상 2층 | 지상 2층 | 5998771 | KBIMS-스테인리스 스틸_도금, KBIMS-유리
5433527 | 지상 3층 | 지상 3층 | 5998918
5433529 | 지상 5층 | 지상 5층 | 5999356 | KBIMS-스테인리스 스틸_도금, KBIMS-유리
5433531 | 지상 6층 | 지상 6층 | 5999548 | KBIMS-스테인리스 스틸_도금, KBIMS-유리
5433533 | 지상 7층 | 지상 7층 | 5999768 | KBIMS-스테인리스 스틸_도금, KBIMS-유리
5433535 | 지상 8층 | 지상 8층 | 5999969 | KBIMS-스테인리스 스틸_도금, KBIMS-유리
5433537 | 지상 9층 | 지상 9층 | 6000137 | KBIMS-스테인리스 스틸_도금, KBIMS-유리
5433539 | 지상 10층 | 지상 10층 | 6000353

# IfcWindow: WD842-2단 하부 더블 프로젝트 창(스테인리스 스틸):WD842-2단 하부 더블 프로젝트 창(스테인리스 스틸)_2000x1800mm (18)
Type - ParameterTakesPrecedence: no; Sizeable: no; Material: KBIMS-스테인리스 스틸_도금 (4), KBIMS-유리 (3)
Type - ID 데이터(Type) - OmniClass 번호: 23.30.20.00; OmniClass 제목: Windows; 유형 마크: 54; 유형 이름: WD842-2단 하부 더블 프로젝트 창(스테인리스 스틸)_2000x1800mm; 유형 해설: AW
Type - 그래픽(Type) - 상부개폐: no; 우측개폐: no; 좌측개폐: no; 회전형_상하/좌우: no; 하부개폐: no
Type - 기타(Type) - 카테고리: 창; KBIMS-부위코드: E334; 방화여부: yes; 조달청표준공사코드: ALB230; 패널유형: triple; 패밀리 이름: WD842-2단 하부 더블 프로젝트 창(스테인리스 스틸)
Type - 시공(Type) - 벽 마무리: 호스트별
Type - 재료 및 마감재(Type) - 창틀 재료: KBIMS-스테인리스 스틸_도금; 패널 재료: KBIMS-유리; 프레임 재료: KBIMS-스테인리스 스틸_도금
Type - 치수(Type) - 구조체 간격: 0 mm; 중심이동_창틀: 0 mm; 높이: 1800 mm; 높이_상부창(고정): 1300 mm; 높이_하부창: 500 mm; 대략적인 높이: 1800 mm; 대략적인 폭: 2000 mm; 중심이동_패널 상부: 0 mm; 중심이동_패널 하부: 45 mm; 창틀 두께: 125 mm; 창틀 폭: 60 mm; 패널 두께: 12 mm; 폭: 2000 mm; 프레임 두께: 30 mm; 프레임 폭: 50 mm
Type - 해석 특성(Type) - 열 특성 정의 기준: 개략적 유형; 해석 시공: <없음>
Type - Pset_WindowCommon - IsExternal: no
OverallHeight: 1800 mm; OverallWidth: 2000 mm
Pset_QuantityTakeOff - Reference: WD842-2단 하부 더블 프로젝트 창(스테인리스 스틸)_2000x1800mm
Pset_WindowCommon - Reference: WD842-2단 하부 더블 프로젝트 창(스테인리스 스틸)_2000x1800mm
BaseQuantities - Height: 1800 mm; Width: 2000 mm; Area: 3.6 m2
공정 - 생성 공정: 새 구성
기타 - 카테고리: 창; 유형: WD842-2단 하부 더블 프로젝트 창(스테인리스 스틸)_2000x1800mm; 유형 ID: 7468501; 패밀리: WD842-2단 하부 더블 프로젝트 창(스테인리스 스틸); 패밀리 및 유형: WD842-2단 하부 더블 프로젝트 창(스테인리스 스틸): WD842-2단 하부 더블 프로젝트 창(스테인리스 스틸)_2000x1800mm; 창의개폐비: 100
치수 - 면적: 5.10973 m2; 체적: 0.113019 m3
Name (WD842-2단 하부 더블 프로젝트 창(스테인리스 스틸):WD842-2단 하부 더블 프로젝트 창(스테인리스 스틸)_2000x1800mm:...) | In | 레벨 | 씰 높이 (mm) | 호스트 ID | 헤드 높이 (mm) | Material
5410182 | 지상 4층 | 지상 4층 | 1000 | 2820733 | 2800 | Pset_WindowCommon - IsExternal: yes
5410962 | 지상 5층 | 지상 5층 | 1000 | 2821235 | 2800 | KBIMS-스테인리스 스틸_도금, KBIMS-유리
5411044 | 지상 6층 | 지상 6층 | 1000 | 2821495 | 2800 | KBIMS-스테인리스 스틸_도금, KBIMS-유리
5411088 | 지상 7층 | 지상 7층 | 1000 | 2821691 | 2800 | KBIMS-스테인리스 스틸_도금, KBIMS-유리
5411094 | 지상 8층 | 지상 8층 | 1000 | 2822037 | 2800 | KBIMS-스테인리스 스틸_도금, KBIMS-유리
5411100 | 지상 9층 | 지상 9층 | 1000 | 2822243 | 2800 | KBIMS-스테인리스 스틸_도금, KBIMS-유리
5411236 | 지상 10층 | 지상 10층 | 1000 | 2822429 | 2800
5433352 | 지상 4층 | 지상 4층 | 1000 | 2820713 | 2800
5433396 | 지상 5층 | 지상 5층 | 1000 | 2821215 | 2800 | KBIMS-스테인리스 스틸_도금, KBIMS-유리
5433398 | 지상 6층 | 지상 6층 | 1000 | 2821475 | 2800 | KBIMS-스테인리스 스틸_도금, KBIMS-유리
5433400 | 지상 7층 | 지상 7층 | 1000 | 2821671 | 2800 | KBIMS-스테인리스 스틸_도금, KBIMS-유리
5433402 | 지상 8층 | 지상 8층 | 1000 | 2822017 | 2800 | KBIMS-스테인리스 스틸_도금, KBIMS-유리
5433404 | 지상 9층 | 지상 9층 | 1000 | 2822223 | 2800 | KBIMS-스테인리스 스틸_도금, KBIMS-유리
5433406 | 지상 10층 | 지상 10층 | 1000 | 7721671 | 2800
5433460 | 지상 1층 | 지상 1층 | 1000 | 2818398 | 2800 | KBIMS-스테인리스 스틸_도금, KBIMS-유리
5433619 | 지상 2층 | 지상 2층 | 1000 | 2820046 | 2800 | KBIMS-스테인리스 스틸_도금, KBIMS-유리
5433621 | 지상 3층 | 지상 3층 | 1000 | 2820463 | 2800 | KBIMS-스테인리스 스틸_도금, KBIMS-유리
5916752 | 지상 1층 | 지상 1층 | -500 | 2819460 | 1300 | KBIMS-스테인리스 스틸_도금, KBIMS-유리
